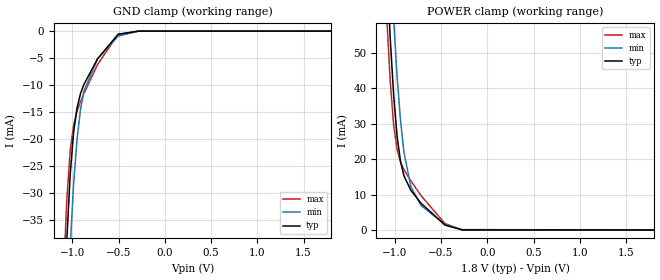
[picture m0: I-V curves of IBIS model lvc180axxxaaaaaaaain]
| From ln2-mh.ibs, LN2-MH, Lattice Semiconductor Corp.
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|   Model lvc180axxxaaaaaaaain
[Model] lvc180axxxaaaaaaaain
Model_type Input
Polarity   Non-Inverting
Enable   Active-High
Vinl =  0.630V
Vinh =  1.170V
C_comp   5.000pF   4.000pF   5.500pF
[Temperature Range]   25.000   0.125k   -40.000
[Voltage Range]   1.800V   1.710V   1.890V
[C Comp Corner]
C_comp   5.000pF   4.000pF   5.500pF
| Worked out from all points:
|   GND clamp passes 1 mA (typ) near -0.54 V on its own axis
|   POWER clamp passes 1 mA (typ) near -0.43 V on its own axis
[GND_clamp]
|Voltage   I(typ)   I(min)   I(max)
-1.8V     -593.8mA   -601.6mA   -589.9mA
-1.097V   -55.43mA   -73.28mA   -46.03mA
-1.06V    -38.82mA   -55.14mA   -31.31mA
-1.023V   -26.57mA   -40.02mA   -22.16mA
-986mV    -18.72mA   -28.32mA   -17.41mA
-949mV    -14.23mA   -20.04mA   -14.84mA
-912mV    -11.62mA   -14.6mA    -13.08mA
-875mV    -9.888mA   -11.17mA   -11.57mA
-727mV    -5.132mA   -5.103mA   -6.185mA
-505mV    -593.1uA   -941.9uA   -608.6uA
-283mV    -845.6nA   -11.06uA   -175.4nA
1.8V      0A         0A         0A
[POWER_clamp]
|Voltage   I(typ)   I(min)   I(max)
-1.789V   656.1mA    673.4mA    646.6mA
-1.086V   74.05mA    100.3mA    59.6mA
-1.049V   53.94mA    78.49mA    41.72mA
-1.012V   37.83mA    59.3mA     29.5mA
-975mV    26.39mA    43.25mA    22.68mA
-938mV    19.32mA    30.82mA    19.16mA
-901mV    15.29mA    21.92mA    17.03mA
-827mV    11.23mA    12.27mA    13.9mA
-716mV    7.541mA    6.911mA    9.687mA
-457mV    1.37mA     1.553mA    1.792mA
-272mV    21.09uA    99.55uA    12.56uA
1.8V      0A         0A         0A
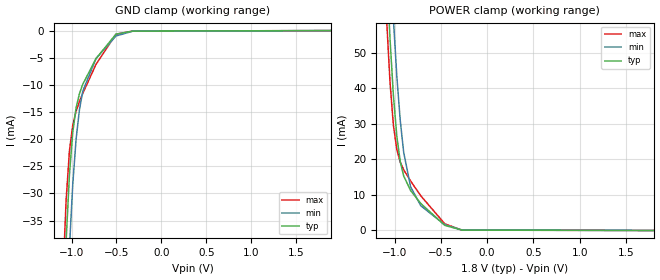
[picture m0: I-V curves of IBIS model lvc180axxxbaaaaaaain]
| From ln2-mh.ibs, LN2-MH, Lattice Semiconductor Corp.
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|   Model lvc180axxxbaaaaaaain
[Model] lvc180axxxbaaaaaaain
Model_type Input
Polarity   Non-Inverting
Enable   Active-High
Vinl =  0.630V
Vinh =  1.170V
C_comp   5.000pF   4.000pF   5.500pF
[Temperature Range]   25.000   0.125k   -40.000
[Voltage Range]   1.800V   1.710V   1.890V
[C Comp Corner]
C_comp   5.000pF   4.000pF   5.500pF
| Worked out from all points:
|   GND clamp passes 1 mA (typ) near -0.53 V on its own axis
|   POWER clamp passes 1 mA (typ) near -0.43 V on its own axis
[GND_clamp]
|Voltage   I(typ)   I(min)   I(max)
-1.8V     -593.8mA   -601.6mA   -589.9mA
-1.097V   -55.44mA   -73.29mA   -46.03mA
-1.06V    -38.82mA   -55.15mA   -31.31mA
-1.023V   -26.58mA   -40.03mA   -22.17mA
-986mV    -18.73mA   -28.33mA   -17.42mA
-949mV    -14.24mA   -20.05mA   -14.86mA
-912mV    -11.64mA   -14.62mA   -13.09mA
-875mV    -9.904mA   -11.18mA   -11.58mA
-727mV    -5.156mA   -5.128mA   -6.207mA
-505mV    -654.2uA   -995.8uA   -670.8uA
-320mV    -95.24uA   -117.6uA   -94.23uA
1.89V     0A         0A         0A
[POWER_clamp]
|Voltage   I(typ)   I(min)   I(max)
-1.789V   656.1mA    673.4mA    646.7mA
-1.086V   74.07mA    100.3mA    59.62mA
-1.049V   53.96mA    78.5mA     41.74mA
-1.012V   37.85mA    59.32mA    29.54mA
-975mV    26.42mA    43.27mA    22.72mA
-938mV    19.35mA    30.85mA    19.2mA
-901mV    15.32mA    21.94mA    17.08mA
-827mV    11.27mA    12.31mA    13.94mA
-716mV    7.586mA    6.949mA    9.737mA
-457mV    1.435mA    1.604mA    1.865mA
-272mV    94.61uA    156.5uA    102.5uA
1.8V      0A         0A         0A
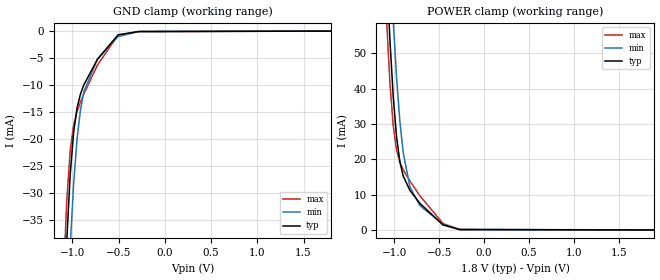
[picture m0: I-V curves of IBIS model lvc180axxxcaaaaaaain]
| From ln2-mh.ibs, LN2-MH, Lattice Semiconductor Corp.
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|   Model lvc180axxxcaaaaaaain
[Model] lvc180axxxcaaaaaaain
Model_type Input
Polarity   Non-Inverting
Enable   Active-High
Vinl =  0.630V
Vinh =  1.170V
C_comp   5.000pF   4.000pF   5.500pF
[Temperature Range]   25.000   0.125k   -40.000
[Voltage Range]   1.800V   1.710V   1.890V
[C Comp Corner]
C_comp   5.000pF   4.000pF   5.500pF
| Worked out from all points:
|   GND clamp passes 1 mA (typ) near -0.53 V on its own axis
|   POWER clamp passes 1 mA (typ) near -0.43 V on its own axis
[GND_clamp]
|Voltage   I(typ)   I(min)   I(max)
-1.8V     -593.8mA   -601.6mA   -589.9mA
-1.097V   -55.46mA   -73.3mA    -46.06mA
-1.06V    -38.85mA   -55.17mA   -31.35mA
-1.023V   -26.61mA   -40.05mA   -22.21mA
-986mV    -18.77mA   -28.35mA   -17.46mA
-949mV    -14.27mA   -20.07mA   -14.9mA
-912mV    -11.67mA   -14.64mA   -13.14mA
-875mV    -9.942mA   -11.21mA   -11.63mA
-727mV    -5.196mA   -5.156mA   -6.26mA
-505mV    -695uA     -1.018mA   -733.5uA
-283mV    -83.17uA   -81.38uA   -98.72uA
1.8V      0A         0A         0A
[POWER_clamp]
|Voltage   I(typ)   I(min)   I(max)
-1.789V   656.1mA    673.4mA    646.6mA
-1.086V   74.06mA    100.3mA    59.61mA
-1.049V   53.95mA    78.5mA     41.72mA
-1.012V   37.83mA    59.31mA    29.51mA
-975mV    26.4mA     43.26mA    22.69mA
-938mV    19.33mA    30.83mA    19.17mA
-901mV    15.3mA     21.93mA    17.04mA
-827mV    11.24mA    12.29mA    13.91mA
-716mV    7.56mA     6.932mA    9.703mA
-457mV    1.417mA    1.598mA    1.834mA
-272mV    110.3uA    182.5uA    103.2uA
1.89V     0A         0A         0A
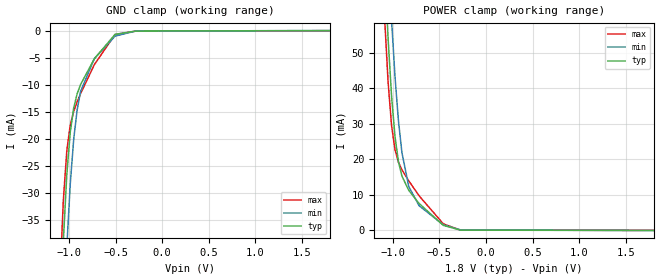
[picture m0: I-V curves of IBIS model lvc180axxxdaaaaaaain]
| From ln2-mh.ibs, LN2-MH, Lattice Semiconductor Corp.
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|   Model lvc180axxxdaaaaaaain
[Model] lvc180axxxdaaaaaaain
Model_type Input
Polarity   Non-Inverting
Enable   Active-High
Vinl =  0.630V
Vinh =  1.170V
C_comp   5.000pF   4.000pF   5.500pF
[Temperature Range]   25.000   0.125k   -40.000
[Voltage Range]   1.800V   1.710V   1.890V
[C Comp Corner]
C_comp   5.000pF   4.000pF   5.500pF
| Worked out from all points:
|   GND clamp passes 1 mA (typ) near -0.53 V on its own axis
|   POWER clamp passes 1 mA (typ) near -0.43 V on its own axis
[GND_clamp]
|Voltage   I(typ)   I(min)   I(max)
-1.8V     -593.8mA   -601.6mA   -589.9mA
-1.097V   -55.46mA   -73.3mA    -46.06mA
-1.06V    -38.85mA   -55.17mA   -31.35mA
-1.023V   -26.61mA   -40.05mA   -22.21mA
-986mV    -18.77mA   -28.35mA   -17.46mA
-949mV    -14.27mA   -20.07mA   -14.9mA
-912mV    -11.67mA   -14.64mA   -13.14mA
-875mV    -9.942mA   -11.21mA   -11.63mA
-727mV    -5.196mA   -5.156mA   -6.26mA
-505mV    -695uA     -1.018mA   -733.5uA
-283mV    -83.17uA   -81.38uA   -98.72uA
1.8V      -13.14nA   0A         -27.62uA
[POWER_clamp]
|Voltage   I(typ)   I(min)   I(max)
-1.789V   656.1mA    673.4mA    646.7mA
-1.086V   74.07mA    100.3mA    59.62mA
-1.049V   53.96mA    78.5mA     41.74mA
-1.012V   37.85mA    59.32mA    29.54mA
-975mV    26.42mA    43.27mA    22.72mA
-938mV    19.35mA    30.85mA    19.2mA
-901mV    15.32mA    21.94mA    17.08mA
-827mV    11.27mA    12.31mA    13.94mA
-716mV    7.586mA    6.949mA    9.737mA
-457mV    1.435mA    1.604mA    1.865mA
-272mV    94.61uA    156.5uA    102.5uA
1.8V      0A         0A         28.48uA
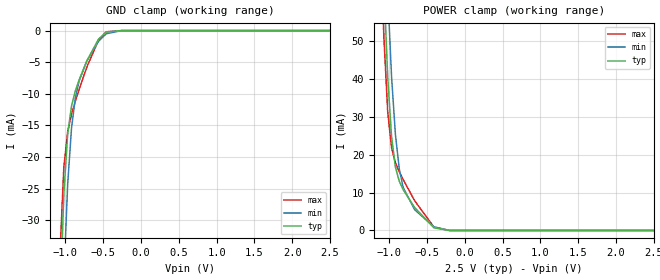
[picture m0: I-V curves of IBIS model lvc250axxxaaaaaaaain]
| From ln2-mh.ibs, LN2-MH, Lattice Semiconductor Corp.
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|   Model lvc250axxxaaaaaaaain
[Model] lvc250axxxaaaaaaaain
Model_type Input
Polarity   Non-Inverting
Enable   Active-High
Vinl =  0.700V
Vinh =  1.700V
C_comp   5.000pF   4.000pF   5.500pF
[Temperature Range]   25.000   0.125k   -40.000
[Voltage Range]   2.500V   2.380V   2.630V
[C Comp Corner]
C_comp   5.000pF   4.000pF   5.500pF
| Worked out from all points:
|   GND clamp passes 1 mA (typ) near -0.54 V on its own axis
|   POWER clamp passes 1 mA (typ) near -0.43 V on its own axis
[GND_clamp]
|Voltage   I(typ)   I(min)   I(max)
-2.5V     -1.192A    -1.195A    -1.19A
-1.072V   -43.75mA   -60.69mA   -35.41mA
-1.021V   -25.99mA   -39.29mA   -21.7mA
-970mV    -16.38mA   -24.32mA   -16mA
-919mV    -11.94mA   -15.42mA   -13.24mA
-868mV    -9.525mA   -10.63mA   -11.17mA
-817mV    -7.753mA   -7.942mA   -9.278mA
-715mV    -4.764mA   -4.767mA   -5.735mA
-562mV    -1.351mA   -1.698mA   -1.532mA
-460mV    -227.7uA   -505.8uA   -189.7uA
-256mV    -345.3nA   -5.519uA   -58.82nA
2.5V      0A         0A         0A
[POWER_clamp]
|Voltage   I(typ)   I(min)   I(max)
-2.498V   1.304A     1.316A     1.297A
-1.121V   95.94mA    122.8mA    80.58mA
-1.07V    64.94mA    90.54mA    51.24mA
-1.019V   40.52mA    62.72mA    31.37mA
-968mV    24.75mA    40.65mA    21.85mA
-917mV    16.76mA    25.36mA    17.89mA
-866mV    13.01mA    16.28mA    15.51mA
-815mV    10.8mA     11.39mA    13.48mA
-662mV    6.034mA    5.465mA    7.841mA
-407mV    709.3uA    963.6uA    895.3uA
-203mV    1.87uA     18.14uA    588nA
2.5V      0A         0A         0A
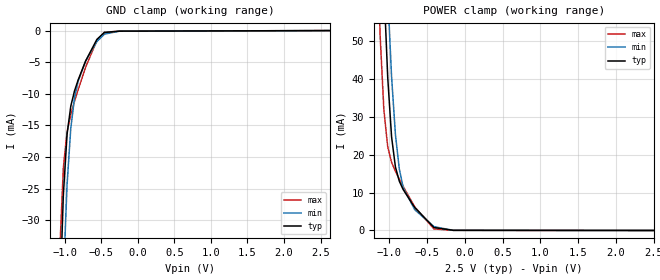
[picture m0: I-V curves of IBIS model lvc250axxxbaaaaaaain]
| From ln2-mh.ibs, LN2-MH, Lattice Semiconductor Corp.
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|   Model lvc250axxxbaaaaaaain
[Model] lvc250axxxbaaaaaaain
Model_type Input
Polarity   Non-Inverting
Enable   Active-High
Vinl =  0.700V
Vinh =  1.700V
C_comp   5.000pF   4.000pF   5.500pF
[Temperature Range]   25.000   0.125k   -40.000
[Voltage Range]   2.500V   2.380V   2.630V
[C Comp Corner]
C_comp   5.000pF   4.000pF   5.500pF
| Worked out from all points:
|   GND clamp passes 1 mA (typ) near -0.53 V on its own axis
|   POWER clamp passes 1 mA (typ) near -0.42 V on its own axis
[GND_clamp]
|Voltage   I(typ)   I(min)   I(max)
-2.5V     -1.192A    -1.195A    -1.19A
-1.072V   -43.76mA   -60.69mA   -35.42mA
-1.021V   -26mA      -39.3mA    -21.71mA
-970mV    -16.39mA   -24.33mA   -16.01mA
-919mV    -11.95mA   -15.43mA   -13.26mA
-868mV    -9.541mA   -10.65mA   -11.19mA
-817mV    -7.772mA   -7.962mA   -9.295mA
-715mV    -4.79mA    -4.793mA   -5.758mA
-562mV    -1.398mA   -1.741mA   -1.577mA
-460mV    -303uA     -570.5uA   -268.1uA
-256mV    -93.09uA   -97.56uA   -93.82uA
2.63V     0A         0A         0A
[POWER_clamp]
|Voltage   I(typ)   I(min)   I(max)
-2.498V   1.304A     1.316A     1.252A
-1.121V   95.95mA    122.8mA    52.26mA
-1.07V    64.96mA    90.55mA    31.97mA
-1.019V   40.55mA    62.74mA    22.12mA
-968mV    24.78mA    40.67mA    18.05mA
-917mV    16.8mA     25.38mA    15.64mA
-866mV    13.05mA    16.31mA    13.61mA
-815mV    10.84mA    11.42mA    11.66mA
-662mV    6.081mA    5.505mA    6.248mA
-407mV    780.9uA    1.018mA    403.1uA
-152mV    41.74uA    39.57uA    33.52uA
2.5V      0A         0A         0A
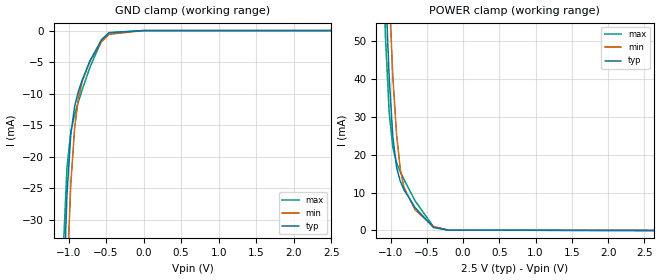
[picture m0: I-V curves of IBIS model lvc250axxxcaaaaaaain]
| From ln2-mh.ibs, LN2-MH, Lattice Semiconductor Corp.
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|   Model lvc250axxxcaaaaaaain
[Model] lvc250axxxcaaaaaaain
Model_type Input
Polarity   Non-Inverting
Enable   Active-High
Vinl =  0.700V
Vinh =  1.700V
C_comp   5.000pF   4.000pF   5.500pF
[Temperature Range]   25.000   0.125k   -40.000
[Voltage Range]   2.500V   2.380V   2.630V
[C Comp Corner]
C_comp   5.000pF   4.000pF   5.500pF
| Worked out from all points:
|   GND clamp passes 1 mA (typ) near -0.53 V on its own axis
|   POWER clamp passes 1 mA (typ) near -0.42 V on its own axis
[GND_clamp]
|Voltage   I(typ)   I(min)   I(max)
-2.5V     -1.192A    -1.195A    -1.19A
-1.072V   -43.78mA   -60.71mA   -35.45mA
-1.021V   -26.03mA   -39.32mA   -21.75mA
-970mV    -16.43mA   -24.35mA   -16.06mA
-919mV    -11.99mA   -15.46mA   -13.3mA
-868mV    -9.579mA   -10.68mA   -11.24mA
-817mV    -7.81mA    -7.99mA    -9.346mA
-715mV    -4.829mA   -4.821mA   -5.811mA
-562mV    -1.439mA   -1.766mA   -1.637mA
-460mV    -340.1uA   -588uA     -329.6uA
-1mV      -322.6nA   -546.3nA   -344.6nA
2.5V      0A         0A         0A
[POWER_clamp]
|Voltage   I(typ)   I(min)   I(max)
-2.498V   1.304A     1.316A     1.297A
-1.121V   95.94mA    122.8mA    80.59mA
-1.07V    64.94mA    90.54mA    51.24mA
-1.019V   40.53mA    62.73mA    31.37mA
-968mV    24.76mA    40.66mA    21.86mA
-917mV    16.77mA    25.37mA    17.9mA
-866mV    13.02mA    16.29mA    15.53mA
-815mV    10.81mA    11.4mA     13.5mA
-662mV    6.057mA    5.49mA     7.861mA
-407mV    767.3uA    1.018mA    949.7uA
-203mV    93.35uA    107.9uA    92.84uA
2.63V     0A         0A         0A
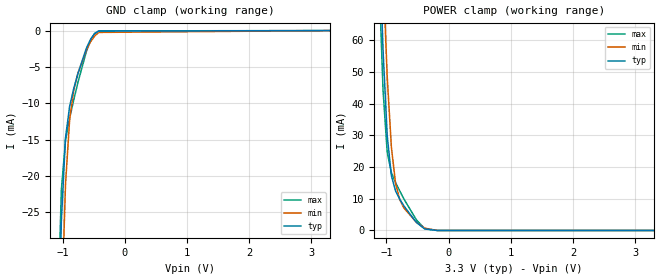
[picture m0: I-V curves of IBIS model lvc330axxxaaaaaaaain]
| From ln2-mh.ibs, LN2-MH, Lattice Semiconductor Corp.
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|   Model lvc330axxxaaaaaaaain
[Model] lvc330axxxaaaaaaaain
Model_type Input
Polarity   Non-Inverting
Enable   Active-High
Vinl =  0.800V
Vinh =  2.000V
C_comp   5.000pF   4.000pF   5.500pF
[Temperature Range]   25.000   0.125k   -40.000
[Voltage Range]   3.300V   3.140V   3.470V
[C Comp Corner]
C_comp   5.000pF   4.000pF   5.500pF
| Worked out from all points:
|   GND clamp passes 1 mA (typ) near -0.54 V on its own axis
|   POWER clamp passes 1 mA (typ) near -0.43 V on its own axis
[GND_clamp]
|Voltage   I(typ)   I(min)   I(max)
-3.3V     -1.888A    -1.888A    -1.884A
-1.089V   -51.51mA   -69.13mA   -42.36mA
-1.022V   -26.27mA   -39.65mA   -21.92mA
-955mV    -14.73mA   -21.14mA   -15.11mA
-888mV    -10.38mA   -12.17mA   -12.02mA
-821mV    -7.911mA   -8.124mA   -9.484mA
-754mV    -5.878mA   -5.822mA   -7.087mA
-620mV    -2.453mA   -2.701mA   -2.895mA
-553mV    -1.209mA   -1.563mA   -1.356mA
-486mV    -407.8uA   -735.6uA   -389uA
-419mV    -74.09uA   -251uA     -44.51uA
3.3V      0A         0A         0A
[POWER_clamp]
|Voltage   I(typ)   I(min)   I(max)
-3.266V   2.018A     2.026A     2.011A
-1.122V   96.65mA    123.5mA    81.29mA
-1.055V   57.01mA    81.9mA     44.37mA
-988mV    29.96mA    48.56mA    24.75mA
-921mV    17.31mA    26.37mA    18.28mA
-854mV    12.53mA    14.91mA    15.15mA
-787mV    9.913mA    9.785mA    12.51mA
-720mV    7.777mA    7.123mA    9.98mA
-519mV    2.548mA    2.55mA     3.358mA
-385mV    484uA      741.5uA    589.3uA
-184mV    1.02uA     11.17uA    291.2nA
3.3V      0A         0A         0A
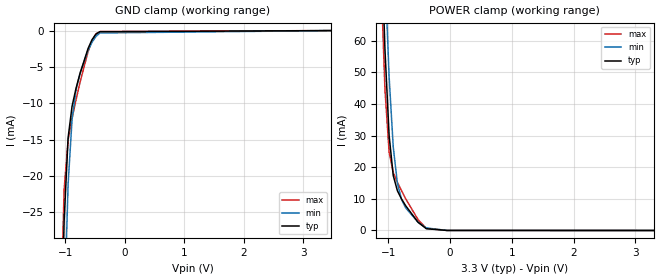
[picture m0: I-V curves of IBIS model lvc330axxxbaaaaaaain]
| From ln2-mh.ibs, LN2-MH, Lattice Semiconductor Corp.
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|   Model lvc330axxxbaaaaaaain
[Model] lvc330axxxbaaaaaaain
Model_type Input
Polarity   Non-Inverting
Enable   Active-High
Vinl =  0.800V
Vinh =  2.000V
C_comp   5.000pF   4.000pF   5.500pF
[Temperature Range]   25.000   0.125k   -40.000
[Voltage Range]   3.300V   3.140V   3.470V
[C Comp Corner]
C_comp   5.000pF   4.000pF   5.500pF
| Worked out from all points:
|   GND clamp passes 1 mA (typ) near -0.53 V on its own axis
|   POWER clamp passes 1 mA (typ) near -0.42 V on its own axis
[GND_clamp]
|Voltage   I(typ)   I(min)   I(max)
-3.3V     -1.888A    -1.888A    -1.884A
-1.089V   -51.51mA   -69.14mA   -42.37mA
-1.022V   -26.28mA   -39.66mA   -21.93mA
-955mV    -14.75mA   -21.16mA   -15.12mA
-888mV    -10.4mA    -12.19mA   -12.04mA
-821mV    -7.931mA   -8.144mA   -9.504mA
-754mV    -5.902mA   -5.847mA   -7.11mA
-620mV    -2.489mA   -2.736mA   -2.929mA
-553mV    -1.258mA   -1.608mA   -1.404mA
-486mV    -475.1uA   -794uA     -458uA
-419mV    -159.8uA   -326.1uA   -133.8uA
3.47V     0A         0A         0A
[POWER_clamp]
|Voltage   I(typ)   I(min)   I(max)
-3.266V   2.018A     2.026A     2.011A
-1.122V   96.67mA    123.5mA    81.31mA
-1.055V   57.03mA    81.91mA    44.39mA
-988mV    29.99mA    48.58mA    24.79mA
-921mV    17.35mA    26.39mA    18.32mA
-854mV    12.57mA    14.94mA    15.2mA
-787mV    9.955mA    9.821mA    12.56mA
-720mV    7.821mA    7.161mA    10.03mA
-519mV    2.605mA    2.596mA    3.423mA
-385mV    558.9uA    797uA      677.4uA
-50mV     13.41uA    11.82uA    16.07uA
3.3V      0A         0A         0A
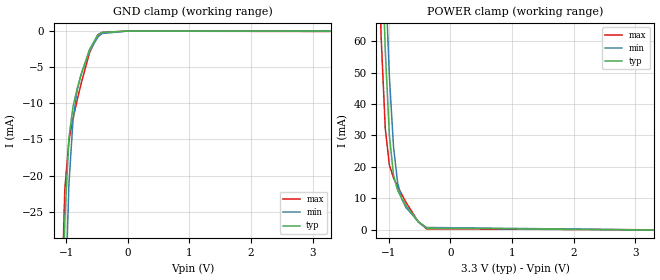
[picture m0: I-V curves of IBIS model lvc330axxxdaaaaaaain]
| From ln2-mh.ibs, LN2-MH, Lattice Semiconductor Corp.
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|   Model lvc330axxxdaaaaaaain
[Model] lvc330axxxdaaaaaaain
Model_type Input
Polarity   Non-Inverting
Enable   Active-High
Vinl =  0.800V
Vinh =  2.000V
C_comp   5.000pF   4.000pF   5.500pF
[Temperature Range]   25.000   0.125k   -40.000
[Voltage Range]   3.300V   3.140V   3.470V
[C Comp Corner]
C_comp   5.000pF   4.000pF   5.500pF
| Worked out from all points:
|   GND clamp passes 1 mA (typ) near -0.53 V on its own axis
|   POWER clamp passes 1 mA (typ) near -0.42 V on its own axis
[GND_clamp]
|Voltage   I(typ)   I(min)   I(max)
-3.3V     -1.888A    -1.888A    -1.884A
-1.089V   -51.53mA   -69.15mA   -42.39mA
-1.022V   -26.3mA    -39.68mA   -21.97mA
-955mV    -14.78mA   -21.18mA   -15.17mA
-888mV    -10.43mA   -12.22mA   -12.09mA
-821mV    -7.968mA   -8.171mA   -9.552mA
-754mV    -5.939mA   -5.874mA   -7.16mA
-620mV    -2.529mA   -2.762mA   -2.986mA
-486mV    -514.7uA   -814.1uA   -521uA
-419mV    -189.1uA   -337.4uA   -186.7uA
-17mV     -4.857uA   -4.628uA   -5.666uA
3.3V      -228.2nA   0A         -51.2uA
[POWER_clamp]
|Voltage   I(typ)   I(min)   I(max)
-3.266V   2.018A     2.026A     1.981A
-1.189V   143.8mA    170.5mA    104.3mA
-1.122V   96.67mA    123.5mA    61.29mA
-1.055V   57.03mA    81.91mA    32.26mA
-988mV    29.99mA    48.58mA    20.59mA
-921mV    17.35mA    26.39mA    16.54mA
-854mV    12.57mA    14.94mA    13.81mA
-787mV    9.955mA    9.821mA    11.28mA
-720mV    7.821mA    7.161mA    8.829mA
-519mV    2.605mA    2.596mA    2.57mA
-385mV    558.9uA    797uA      357.4uA
3.3V      0A         0A         51.61uA
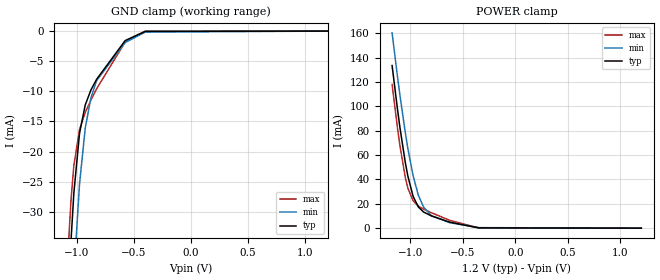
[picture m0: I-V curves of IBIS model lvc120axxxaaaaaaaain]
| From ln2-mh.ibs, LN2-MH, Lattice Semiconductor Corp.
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|   Model lvc120axxxaaaaaaaain
[Model] lvc120axxxaaaaaaaain
Model_type Input
Polarity   Non-Inverting
Enable   Active-High
Vinl =  0.420V
Vinh =  0.780V
C_comp   5.000pF   4.000pF   5.500pF
[Temperature Range]   25.000   0.125k   -40.000
[Voltage Range]   1.200V   1.140V   1.260V
[C Comp Corner]
C_comp   5.000pF   4.000pF   5.500pF
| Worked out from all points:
|   GND clamp passes 1 mA (typ) near -0.54 V on its own axis
|   POWER clamp passes 1 mA (typ) near -0.43 V on its own axis
[GND_clamp]
|Voltage   I(typ)   I(min)   I(max)
-1.2V     -117.2mA   -135mA     -107.6mA
-1.1V     -56.86mA   -74.77mA   -47.33mA
-1.075V   -44.97mA   -62.07mA   -36.48mA
-1.05V    -34.95mA   -50.63mA   -28.14mA
-1.025V   -26.98mA   -40.64mA   -22.36mA
-975mV    -16.96mA   -25.39mA   -16.34mA
-925mV    -12.26mA   -16.11mA   -13.51mA
-875mV    -9.771mA   -11.05mA   -11.44mA
-825mV    -7.989mA   -8.223mA   -9.563mA
-575mV    -1.572mA   -1.892mA   -1.811mA
-400mV    -42.89uA   -174.2uA   -23.24uA
1.2V      54.17pA    0A         0A
[POWER_clamp]
|Voltage   I(typ)   I(min)   I(max)
-1.175V   133.4mA    160.2mA    117.9mA
-1.125V   98.47mA    125.3mA    83.04mA
-1.1V     82.4mA     108.9mA    67.43mA
-1.05V    54.25mA    78.88mA    41.92mA
-1.025V   42.77mA    65.54mA    32.88mA
-975mV    26.16mA    43.08mA    22.4mA
-925mV    17.39mA    27.08mA    18.05mA
-875mV    13.26mA    17.28mA    15.6mA
-800mV    10.04mA    10.22mA    12.64mA
-625mV    4.901mA    4.474mA    6.406mA
-350mV    221.2uA    440uA      240.2uA
1.2V      0A         0A         0A
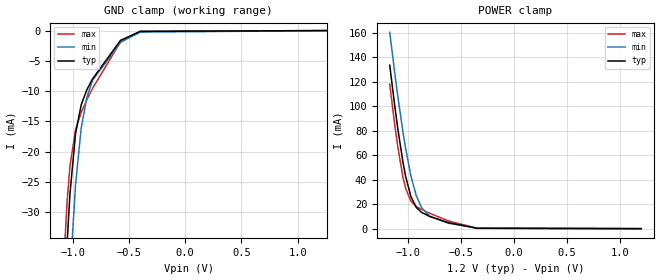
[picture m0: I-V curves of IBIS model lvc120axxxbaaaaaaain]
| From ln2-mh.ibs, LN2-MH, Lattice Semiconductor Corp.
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|   Model lvc120axxxbaaaaaaain
[Model] lvc120axxxbaaaaaaain
Model_type Input
Polarity   Non-Inverting
Enable   Active-High
Vinl =  0.420V
Vinh =  0.780V
C_comp   5.000pF   4.000pF   5.500pF
[Temperature Range]   25.000   0.125k   -40.000
[Voltage Range]   1.200V   1.140V   1.260V
[C Comp Corner]
C_comp   5.000pF   4.000pF   5.500pF
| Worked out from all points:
|   GND clamp passes 1 mA (typ) near -0.53 V on its own axis
|   POWER clamp passes 1 mA (typ) near -0.43 V on its own axis
[GND_clamp]
|Voltage   I(typ)   I(min)   I(max)
-1.2V     -117.2mA   -135mA     -107.6mA
-1.1V     -56.86mA   -74.78mA   -47.33mA
-1.075V   -44.98mA   -62.07mA   -36.48mA
-1.05V    -34.95mA   -50.64mA   -28.16mA
-1.025V   -26.99mA   -40.65mA   -22.37mA
-975mV    -16.97mA   -25.4mA    -16.35mA
-925mV    -12.28mA   -16.12mA   -13.52mA
-875mV    -9.786mA   -11.06mA   -11.45mA
-825mV    -8.006mA   -8.242mA   -9.578mA
-575mV    -1.614mA   -1.931mA   -1.851mA
-400mV    -128.6uA   -250.2uA   -111.6uA
1.26V     0A         0A         0A
[POWER_clamp]
|Voltage   I(typ)   I(min)   I(max)
-1.175V   133.4mA    160.2mA    117.9mA
-1.125V   98.48mA    125.3mA    83.05mA
-1.1V     82.42mA    109mA      67.45mA
-1.05V    54.27mA    78.9mA     41.95mA
-1.025V   42.79mA    65.55mA    32.91mA
-975mV    26.19mA    43.1mA     22.44mA
-925mV    17.43mA    27.1mA     18.09mA
-875mV    13.3mA     17.31mA    15.65mA
-800mV    10.08mA    10.25mA    12.68mA
-625mV    4.949mA    4.514mA    6.461mA
-350mV    298.6uA    495.9uA    334.2uA
1.2V      0A         0A         0A
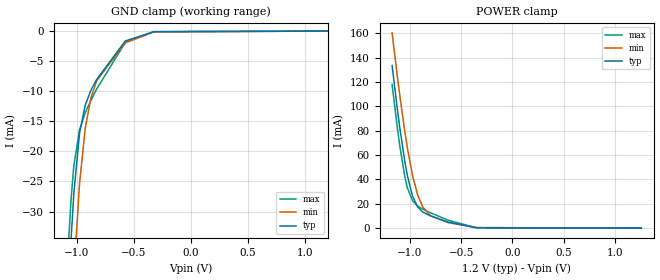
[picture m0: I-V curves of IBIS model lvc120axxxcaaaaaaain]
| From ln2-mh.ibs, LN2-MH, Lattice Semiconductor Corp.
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|   Model lvc120axxxcaaaaaaain
[Model] lvc120axxxcaaaaaaain
Model_type Input
Polarity   Non-Inverting
Enable   Active-High
Vinl =  0.420V
Vinh =  0.780V
C_comp   5.000pF   4.000pF   5.500pF
[Temperature Range]   25.000   0.125k   -40.000
[Voltage Range]   1.200V   1.140V   1.260V
[C Comp Corner]
C_comp   5.000pF   4.000pF   5.500pF
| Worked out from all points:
|   GND clamp passes 1 mA (typ) near -0.53 V on its own axis
|   POWER clamp passes 1 mA (typ) near -0.43 V on its own axis
[GND_clamp]
|Voltage   I(typ)   I(min)   I(max)
-1.2V     -117.3mA   -135mA     -107.6mA
-1.1V     -56.88mA   -74.79mA   -47.36mA
-1.075V   -45mA      -62.09mA   -36.51mA
-1.05V    -34.98mA   -50.66mA   -28.19mA
-1.025V   -27.02mA   -40.67mA   -22.41mA
-975mV    -17.01mA   -25.43mA   -16.4mA
-925mV    -12.31mA   -16.15mA   -13.57mA
-875mV    -9.824mA   -11.09mA   -11.5mA
-825mV    -8.045mA   -8.27mA    -9.63mA
-575mV    -1.656mA   -1.957mA   -1.911mA
-325mV    -96.48uA   -108.8uA   -113uA
1.2V      0A         0A         0A
[POWER_clamp]
|Voltage   I(typ)   I(min)   I(max)
-1.175V   133.4mA    160.2mA    117.9mA
-1.125V   98.47mA    125.3mA    83.04mA
-1.1V     82.41mA    108.9mA    67.44mA
-1.05V    54.26mA    78.89mA    41.93mA
-1.025V   42.78mA    65.54mA    32.88mA
-975mV    26.17mA    43.08mA    22.41mA
-925mV    17.4mA     27.09mA    18.06mA
-875mV    13.27mA    17.29mA    15.61mA
-800mV    10.05mA    10.23mA    12.65mA
-625mV    4.925mA    4.5mA      6.427mA
-350mV    294.1uA    504.6uA    312.4uA
1.26V     0A         0A         0A
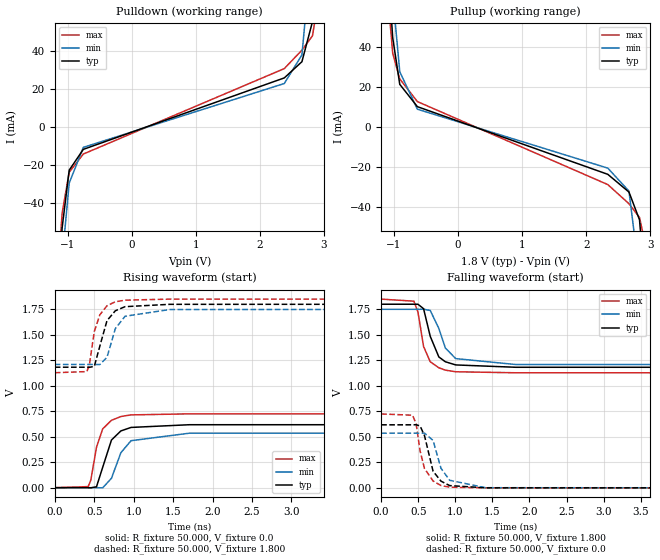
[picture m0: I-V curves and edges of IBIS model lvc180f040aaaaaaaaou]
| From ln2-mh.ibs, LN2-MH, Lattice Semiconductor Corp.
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|   Model lvc180f040aaaaaaaaou
[Model] lvc180f040aaaaaaaaou
Model_type Output
Polarity   Non-Inverting
Enable   Active-High
Vmeas =  0.900V
Cref =  0.0F
Rref =  1.000M
Vref =  0.0V
C_comp   5.000pF   4.000pF   5.500pF
[Temperature Range]   25.000   0.125k   -40.000
[Voltage Range]   1.800V   1.750V   1.850V
[C Comp Corner]
C_comp   5.000pF   4.000pF   5.500pF
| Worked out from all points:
|   slope of the pulldown table from 0 to 0.27 V, typ, clamps not added: 97.6 ohm
|   slope of the pullup table from 0 to 0.27 V, typ, clamps not added: 97.7 ohm
|   rising waveform, R_fixture 50.000, V_fixture 0.0: 20-80 % time 157ps typ, 190ps min, 135ps max; typ from 0 V to 0.618 V
|   rising waveform, R_fixture 50.000, V_fixture 1.800: 20-80 % time 139ps typ, 157ps min, 126ps max; typ from 1.18 V to 1.8 V
|   falling waveform, R_fixture 50.000, V_fixture 1.800: 20-80 % time 144ps typ, 170ps min, 127ps max; typ from 1.8 V to 1.18 V
|   falling waveform, R_fixture 50.000, V_fixture 0.0: 20-80 % time 144ps typ, 161ps min, 132ps max; typ from 0.618 V to 0 V
[Pulldown]
|Voltage   I(typ)   I(min)   I(max)
-1.8V     -594.9mA   -602.6mA   -591.2mA
-1.195V   -116.2mA   -133.8mA   -106.9mA
-1.14V    -81.89mA   -99.71mA   -72.47mA
-1.085V   -53.29mA   -69.9mA    -45.55mA
-975mV    -22.88mA   -29.74mA   -23.99mA
-755mV    -11.87mA   -10.81mA   -14.34mA
2.38V     25.94mA    22.97mA    30.86mA
2.655V    34.5mA     38.12mA    40.62mA
2.82V     55.71mA    98.51mA    48.22mA
2.93V     109.9mA    169.2mA    71.45mA
2.985V    147.2mA    209.4mA    100.1mA
3.6V      668.3mA    729.8mA    614.2mA
[Pullup]
|Voltage   I(typ)   I(min)   I(max)
-1.8V     666.6mA    683.8mA    657.3mA
-1.13V    103.9mA    130.4mA    88.94mA
-1.075V   70.36mA    95.55mA    57.33mA
-1.02V    44.5mA     65.73mA    36.8mA
-910mV    21.26mA    27.55mA    23.96mA
-635mV    10.12mA    8.855mA    12.65mA
2.335V    -23.67mA   -20.57mA   -28.79mA
2.665V    -32.52mA   -32.05mA   -38.34mA
2.83V     -46.45mA   -74.63mA   -45.25mA
2.94V     -89.38mA   -135.4mA   -61.6mA
2.995V    -122.2mA   -171.5mA   -85.2mA
3.6V      -597.5mA   -646.3mA   -552.4mA
[Ramp]
| variable   typ   min   max
dV/dt_r   0.371/0.157n   0.322/0.190n   0.435/0.135n
dV/dt_f   0.371/0.144n   0.325/0.170n   0.433/0.127n
R_load = 50.000
[Rising Waveform]
R_fixture= 50.000
V_fixture= 0.0
V_fixture_min= 0.0
V_fixture_max= 0.0
|time   V(typ)   V(min)   V(max)
0s        817.7nV    7.236uV    251.1nV
423ps     -13.81uV   -70.9uV    10.47mV
457ps     -1.411mV   -5.095uV   74.25mV
529ps     8.791mV    -98.04uV   396.8mV
607ps     199mV      -1.754mV   576.5mV
719ps     467.9mV    92.76mV    661.3mV
838ps     556.9mV    343.1mV    698.4mV
967ps     591.2mV    461mV      714.2mV
1.707ns   617.7mV    534.7mV    724.4mV
10ns      617.9mV    535.8mV    724.4mV
[Rising Waveform]
R_fixture= 50.000
V_fixture= 1.800
V_fixture_min= 1.750
V_fixture_max= 1.850
|time   V(typ)   V(min)   V(max)
0s        1.182V     1.209V     1.128V
407ps     1.182V     1.209V     1.139V
439ps     1.181V     1.209V     1.207V
501ps     1.19V      1.209V     1.532V
571ps     1.388V     1.208V     1.696V
662ps     1.639V     1.279V     1.785V
768ps     1.736V     1.561V     1.824V
891ps     1.776V     1.682V     1.84V
1.457ns   1.799V     1.748V     1.85V
10ns      1.8V       1.75V      1.85V
[Falling Waveform]
R_fixture= 50.000
V_fixture= 1.800
V_fixture_min= 1.750
V_fixture_max= 1.850
|time   V(typ)   V(min)   V(max)
0s        1.8V       1.75V      1.85V
441ps     1.8V       1.75V      1.83V
496ps     1.8V       1.75V      1.724V
572ps     1.756V     1.751V     1.385V
662ps     1.485V     1.739V     1.236V
778ps     1.283V     1.562V     1.177V
866ps     1.236V     1.371V     1.154V
1.005ns   1.205V     1.267V     1.138V
1.816ns   1.182V     1.209V     1.128V
10ns      1.182V     1.209V     1.128V
[Falling Waveform]
R_fixture= 50.000
V_fixture= 0.0
V_fixture_min= 0.0
V_fixture_max= 0.0
|time   V(typ)   V(min)   V(max)
0s        617.9mV    535.8mV    724.4mV
424ps     617.9mV    535.7mV    712mV
472ps     618.9mV    535.8mV    626.8mV
525ps     606.9mV    535.9mV    360.6mV
584ps     512.4mV    536.6mV    190.8mV
700ps     163.3mV    464.9mV    67.38mV
807ps     65.62mV    191.2mV    22.62mV
924ps     22.16mV    74.19mV    6.817mV
1.407ns   353.7uV    1.482mV    104.9uV
10ns      12.82uV    23.46uV    7.881uV
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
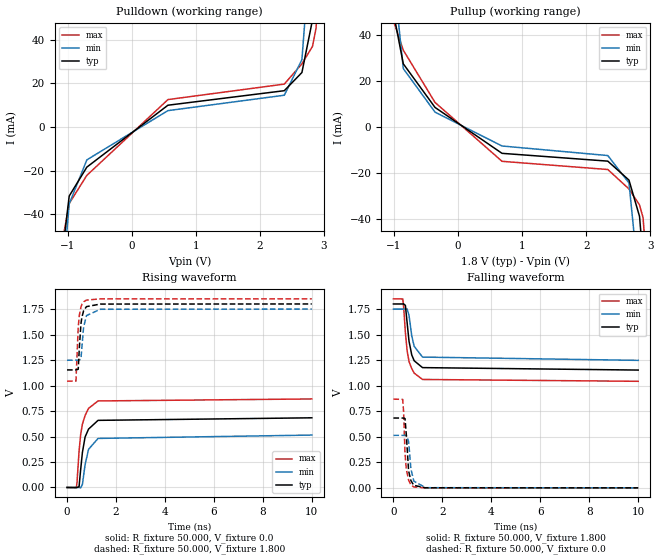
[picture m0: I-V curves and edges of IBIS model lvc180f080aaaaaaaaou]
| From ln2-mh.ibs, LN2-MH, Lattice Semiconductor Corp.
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|   Model lvc180f080aaaaaaaaou
[Model] lvc180f080aaaaaaaaou
Model_type Output
Polarity   Non-Inverting
Enable   Active-High
Vmeas =  0.900V
Cref =  0.0F
Rref =  1.000M
Vref =  0.0V
C_comp   5.000pF   4.000pF   5.500pF
[Temperature Range]   25.000   0.125k   -40.000
[Voltage Range]   1.800V   1.750V   1.850V
[C Comp Corner]
C_comp   5.000pF   4.000pF   5.500pF
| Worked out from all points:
|   slope of the pulldown table from 0 to 0.27 V, typ, clamps not added: 49.4 ohm
|   slope of the pullup table from 0 to 0.27 V, typ, clamps not added: 48.8 ohm
|   rising waveform, R_fixture 50.000, V_fixture 0.0: 20-80 % time 273ps typ, 277ps min, 281ps max; typ from 0 V to 0.683 V
|   rising waveform, R_fixture 50.000, V_fixture 1.800: 20-80 % time 119ps typ, 141ps min, 105ps max; typ from 1.15 V to 1.8 V
|   falling waveform, R_fixture 50.000, V_fixture 1.800: 20-80 % time 233ps typ, 248ps min, 237ps max; typ from 1.8 V to 1.15 V
|   falling waveform, R_fixture 50.000, V_fixture 0.0: 20-80 % time 120ps typ, 141ps min, 107ps max; typ from 0.684 V to 0 V
[Pulldown]
|Voltage   I(typ)   I(min)   I(max)
-1.8V     -595.2mA   -602.9mA   -591.4mA
-1.14V    -85.93mA   -102.5mA   -77.56mA
-1.085V   -58.79mA   -73.44mA   -52.97mA
-975mV    -31.59mA   -35.21mA   -34.99mA
-700mV    -18.35mA   -15.02mA   -22.12mA
565mV     10.01mA    7.529mA    12.59mA
2.38V     16.66mA    14.58mA    19.68mA
2.655V    24.98mA    30.9mA     28.97mA
2.82V     49.1mA     94.77mA    36.95mA
2.875V    73.68mA    128.8mA    45.22mA
2.985V    144.3mA    207.3mA    95.51mA
3.6V      667.3mA    728.9mA    613mA
[Pullup]
|Voltage   I(typ)   I(min)   I(max)
-1.8V     667mA      684.1mA    657.9mA
-1.075V   75.25mA    98.4mA     64.53mA
-1.02V    51.35mA    69.47mA    47.14mA
-855mV    27.49mA    25.43mA    33.42mA
-360mV    8.539mA    6.483mA    10.71mA
685mV     -11.42mA   -8.227mA   -14.89mA
2.335V    -14.81mA   -12.38mA   -18.45mA
2.665V    -23.05mA   -24.29mA   -26.89mA
2.83V     -38.84mA   -70.02mA   -33.87mA
2.885V    -57.42mA   -98.88mA   -39.4mA
2.995V    -118.7mA   -168.9mA   -79.65mA
3.6V      -596mA     -645mA     -550.6mA
[Ramp]
| variable   typ   min   max
dV/dt_r   0.410/0.273n   0.308/0.278n   0.521/0.281n
dV/dt_f   0.388/0.233n   0.301/0.249n   0.484/0.237n
R_load = 50.000
[Rising Waveform]
R_fixture= 50.000
V_fixture= 0.0
V_fixture_min= 0.0
V_fixture_max= 0.0
|time   V(typ)   V(min)   V(max)
0s        838.4nV    7.983uV    249.4nV
381ps     22.78uV    -82.28uV   -3.395mV
407ps     161.6uV    -82.59uV   46.74mV
491ps     6.619mV    120.9uV    352.2mV
556ps     172.5mV    -3.607mV   516.8mV
629ps     344mV      29.85mV    621.2mV
738ps     494.8mV    223.4mV    705.8mV
880ps     572.8mV    374.3mV    776.5mV
1.268ns   658.4mV    481.2mV    848.7mV
10ns      683.4mV    514mV      868.4mV
[Rising Waveform]
R_fixture= 50.000
V_fixture= 1.800
V_fixture_min= 1.750
V_fixture_max= 1.850
|time   V(typ)   V(min)   V(max)
0s        1.153V     1.248V     1.043V
365ps     1.153V     1.249V     1.044V
458ps     1.16V      1.249V     1.574V
503ps     1.368V     1.249V     1.688V
569ps     1.605V     1.261V     1.77V
606ps     1.668V     1.374V     1.795V
679ps     1.734V     1.575V     1.821V
795ps     1.774V     1.686V     1.838V
1.363ns   1.799V     1.748V     1.85V
10ns      1.8V       1.75V      1.85V
[Falling Waveform]
R_fixture= 50.000
V_fixture= 1.800
V_fixture_min= 1.750
V_fixture_max= 1.850
|time   V(typ)   V(min)   V(max)
0s        1.8V       1.75V      1.85V
383ps     1.8V       1.75V      1.849V
423ps     1.8V       1.75V      1.755V
489ps     1.786V     1.75V      1.52V
561ps     1.614V     1.751V     1.341V
638ps     1.435V     1.686V     1.236V
749ps     1.301V     1.489V     1.167V
849ps     1.244V     1.385V     1.123V
1.189ns   1.177V     1.28V      1.061V
10ns      1.153V     1.248V     1.043V
[Falling Waveform]
R_fixture= 50.000
V_fixture= 0.0
V_fixture_min= 0.0
V_fixture_max= 0.0
|time   V(typ)   V(min)   V(max)
0s        683.5mV    514.1mV    868.5mV
379ps     683.3mV    514mV      866mV
415ps     683.2mV    514mV      748.3mV
474ps     678.2mV    513.9mV    340.4mV
525ps     526.6mV    514.3mV    184.5mV
621ps     165.3mV    453.7mV    75.6mV
714ps     71.69mV    185.6mV    29.75mV
832ps     24.5mV     66.72mV    8.971mV
1.312ns   442.1uV    1.7mV      127.8uV
10ns      13.92uV    26.66uV    8.279uV
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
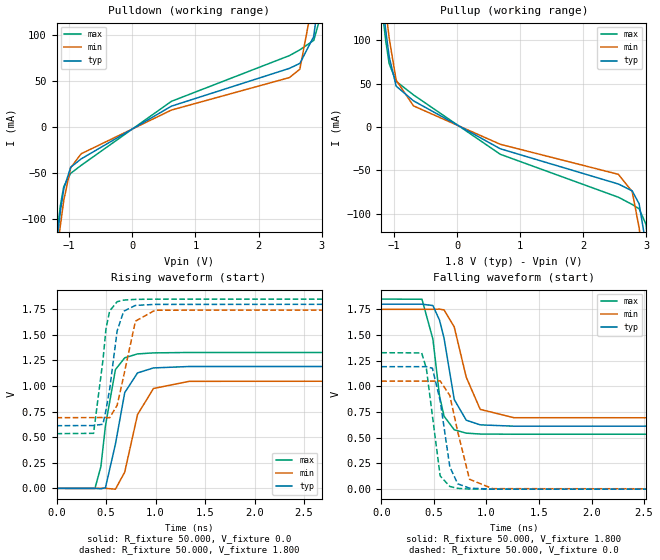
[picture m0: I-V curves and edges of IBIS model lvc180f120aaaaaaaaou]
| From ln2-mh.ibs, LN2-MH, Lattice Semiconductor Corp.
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|   Model lvc180f120aaaaaaaaou
[Model] lvc180f120aaaaaaaaou
Model_type Output
Polarity   Non-Inverting
Enable   Active-High
Vmeas =  0.900V
Cref =  0.0F
Rref =  1.000M
Vref =  0.0V
C_comp   5.000pF   4.000pF   5.500pF
[Temperature Range]   25.000   0.125k   -40.000
[Voltage Range]   1.800V   1.750V   1.850V
[C Comp Corner]
C_comp   5.000pF   4.000pF   5.500pF
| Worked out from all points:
|   slope of the pulldown table from 0 to 0.27 V, typ, clamps not added: 25.1 ohm
|   slope of the pullup table from 0 to 0.27 V, typ, clamps not added: 25 ohm
|   rising waveform, R_fixture 50.000, V_fixture 0.0: 20-80 % time 130ps typ, 162ps min, 106ps max; typ from 0 V to 1.19 V
|   rising waveform, R_fixture 50.000, V_fixture 1.800: 20-80 % time 102ps typ, 125ps min, 84.1ps max; typ from 0.613 V to 1.8 V
|   falling waveform, R_fixture 50.000, V_fixture 1.800: 20-80 % time 124ps typ, 152ps min, 105ps max; typ from 1.8 V to 0.613 V
|   falling waveform, R_fixture 50.000, V_fixture 0.0: 20-80 % time 102ps typ, 125ps min, 87.4ps max; typ from 1.19 V to 0 V
[Pulldown]
|Voltage   I(typ)   I(min)   I(max)
-1.8V     -597.4mA   -605mA     -594.1mA
-1.195V   -124.3mA   -140.2mA   -116.7mA
-1.14V    -92.18mA   -107.5mA   -85.71mA
-1.085V   -67mA      -79.52mA   -64.48mA
-975mV    -43.55mA   -44.03mA   -50.17mA
-810mV    -34.53mA   -28.96mA   -41.56mA
620mV     22.81mA    18.57mA    28.06mA
2.49V     63.9mA     53.9mA     77.77mA
2.655V    69.3mA     62.98mA    84.07mA
2.875V    98.55mA    142.6mA    94.32mA
2.985V    158.3mA    216.8mA    121mA
3.6V      672mA      732.9mA    618.7mA
[Pullup]
|Voltage   I(typ)   I(min)   I(max)
-1.8V     668.3mA    685.3mA    659.4mA
-1.185V   148.6mA    173.6mA    135mA
-1.13V    111.9mA    136.2mA    99.7mA
-1.075V   81.27mA    102.7mA    73.25mA
-965mV    47.35mA    54.25mA    52.81mA
-690mV    30.35mA    24.54mA    37.19mA
685mV     -24.95mA   -19.79mA   -31.31mA
2.555V    -65.6mA    -54.43mA   -80.83mA
2.775V    -73.58mA   -74.31mA   -89.23mA
2.885V    -88.52mA   -116.2mA   -94.25mA
2.995V    -136.9mA   -181.1mA   -112.4mA
3.6V      -603.6mA   -651.1mA   -560.2mA
[Ramp]
| variable   typ   min   max
dV/dt_r   0.715/0.130n   0.631/0.162n   0.797/0.106n
dV/dt_f   0.712/0.124n   0.635/0.152n   0.789/0.105n
R_load = 50.000
[Rising Waveform]
R_fixture= 50.000
V_fixture= 0.0
V_fixture_min= 0.0
V_fixture_max= 0.0
|time   V(typ)   V(min)   V(max)
0s        238.6nV    2.427uV    65.79nV
388ps     116.3uV    -80.63uV   -860.1uV
448ps     -4.418mV   28.73uV    212.3mV
494ps     5.531mV    187.6uV    611.4mV
595ps     432.5mV    -7.851mV   1.161V
689ps     936mV      159.2mV    1.276V
818ps     1.128V     720.3mV    1.314V
979ps     1.177V     976mV      1.324V
1.339ns   1.191V     1.046V     1.328V
10ns      1.192V     1.051V     1.328V
[Rising Waveform]
R_fixture= 50.000
V_fixture= 1.800
V_fixture_min= 1.750
V_fixture_max= 1.850
|time   V(typ)   V(min)   V(max)
0s        612.6mV    690.9mV    534.6mV
374ps     613.9mV    691.7mV    537.8mV
469ps     626.5mV    692.3mV    1.254V
500ps     767.8mV    692.3mV    1.563V
537ps     971.2mV    690.1mV    1.734V
612ps     1.537V     811.2mV    1.824V
678ps     1.731V     1.097V     1.84V
797ps     1.788V     1.634V     1.847V
996ps     1.798V     1.741V     1.849V
10ns      1.8V       1.75V      1.85V
[Falling Waveform]
R_fixture= 50.000
V_fixture= 1.800
V_fixture_min= 1.750
V_fixture_max= 1.850
|time   V(typ)   V(min)   V(max)
0s        1.8V       1.75V      1.85V
387ps     1.8V       1.75V      1.848V
491ps     1.787V     1.75V      1.46V
554ps     1.644V     1.752V     907.8mV
597ps     1.47V      1.745V     710mV
694ps     872.3mV    1.578V     577.9mV
808ps     671.1mV    1.09V      545.1mV
941ps     625.8mV    776.5mV    536.6mV
1.261ns   613.1mV    695.6mV    534.6mV
10ns      612.5mV    690.9mV    534.5mV
[Falling Waveform]
R_fixture= 50.000
V_fixture= 0.0
V_fixture_min= 0.0
V_fixture_max= 0.0
|time   V(typ)   V(min)   V(max)
0s        1.192V     1.051V     1.328V
384ps     1.192V     1.051V     1.326V
429ps     1.192V     1.051V     1.174V
486ps     1.177V     1.051V     716.3mV
560ps     862mV      1.054V     128.9mV
652ps     216.4mV    911mV      26.38mV
727ps     52.23mV    559.4mV    7.809mV
839ps     9.855mV    96.43mV    1.185mV
1.059ns   445.8uV    4.88mV     73.52uV
10ns      2.725uV    7.433uV    1.232uV
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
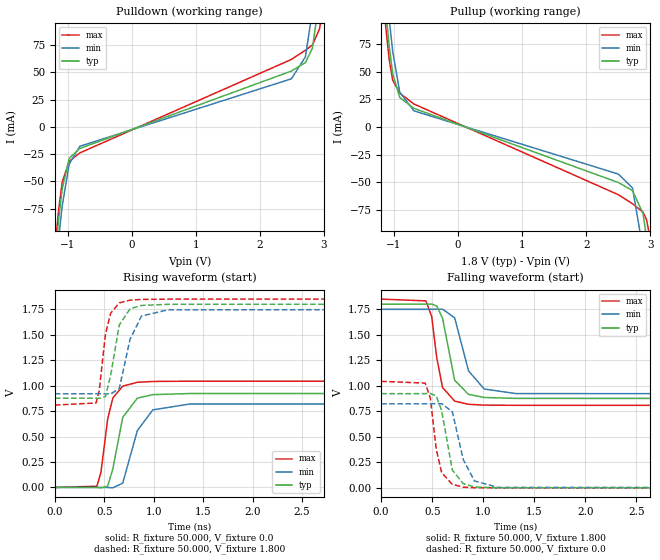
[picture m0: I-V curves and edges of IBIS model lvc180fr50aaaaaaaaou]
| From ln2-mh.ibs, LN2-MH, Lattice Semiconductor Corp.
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|   Model lvc180fr50aaaaaaaaou
[Model] lvc180fr50aaaaaaaaou
Model_type Output
Polarity   Non-Inverting
Enable   Active-High
Vmeas =  0.900V
Cref =  0.0F
Rref =  1.000M
Vref =  0.0V
C_comp   5.000pF   4.000pF   5.500pF
[Temperature Range]   25.000   0.125k   -40.000
[Voltage Range]   1.800V   1.750V   1.850V
[C Comp Corner]
C_comp   5.000pF   4.000pF   5.500pF
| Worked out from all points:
|   slope of the pulldown table from 0 to 0.27 V, typ, clamps not added: 49.2 ohm
|   slope of the pullup table from 0 to 0.27 V, typ, clamps not added: 49.2 ohm
|   rising waveform, R_fixture 50.000, V_fixture 0.0: 20-80 % time 118ps typ, 152ps min, 95.2ps max; typ from 0 V to 0.923 V
|   rising waveform, R_fixture 50.000, V_fixture 1.800: 20-80 % time 99.6ps typ, 120ps min, 83.1ps max; typ from 0.877 V to 1.8 V
|   falling waveform, R_fixture 50.000, V_fixture 1.800: 20-80 % time 104ps typ, 131ps min, 87.9ps max; typ from 1.8 V to 0.877 V
|   falling waveform, R_fixture 50.000, V_fixture 0.0: 20-80 % time 97.3ps typ, 117ps min, 83.7ps max; typ from 0.923 V to 0 V
[Pulldown]
|Voltage   I(typ)   I(min)   I(max)
-1.8V     -596mA     -603.6mA   -592.5mA
-1.195V   -118.6mA   -135.8mA   -109.7mA
-1.14V    -84.81mA   -102.1mA   -76.16mA
-1.085V   -57.12mA   -72.8mA    -50.75mA
-975mV    -28.76mA   -34.06mA   -31.57mA
-810mV    -19.75mA   -17.75mA   -23.83mA
2.49V     51.18mA    44.08mA    61.82mA
2.71V     59.04mA    64.25mA    70.37mA
2.82V     72.29mA    107.1mA    75.18mA
2.93V     119mA      174.8mA    89.91mA
2.985V    154.1mA    214.1mA    112.6mA
3.6V      670.6mA    731.8mA    617mA
[Pullup]
|Voltage   I(typ)   I(min)   I(max)
-1.8V     667.2mA    684.4mA    658mA
-1.13V    106mA      132.1mA    91.59mA
-1.075V   73.12mA    97.61mA    61.16mA
-1.02V    48.26mA    68.32mA    42.26mA
-910mV    26.56mA    31.42mA    30.55mA
-690mV    16.86mA    14.58mA    20.78mA
2.5V      -50.34mA   -42.68mA   -61.37mA
2.72V     -57.55mA   -55.2mA    -69.5mA
2.885V    -78.55mA   -111.1mA   -77.19mA
2.94V     -100.9mA   -142.4mA   -84.11mA
2.995V    -131.1mA   -177.5mA   -101.1mA
3.6V      -601.3mA   -649.3mA   -557.2mA
[Ramp]
| variable   typ   min   max
dV/dt_r   0.554/0.118n   0.494/0.152n   0.627/95.129p
dV/dt_f   0.554/0.105n   0.498/0.131n   0.625/88.091p
R_load = 50.000
[Rising Waveform]
R_fixture= 50.000
V_fixture= 0.0
V_fixture_min= 0.0
V_fixture_max= 0.0
|time   V(typ)   V(min)   V(max)
0s        369.3nV    3.503uV    105.9nV
426ps     -146.4uV   -55.87uV   11.72mV
467ps     -4.11mV    63.69uV    150.3mV
535ps     12.58mV    -554.8uV   673.7mV
587ps     183mV      -4.269mV   879.1mV
687ps     688.3mV    42.43mV    995mV
835ps     877.5mV    558.5mV    1.033V
991ps     911.6mV    761.9mV    1.041V
1.361ns   922.4mV    819.1mV    1.044V
10ns      923.2mV    823.7mV    1.044V
[Rising Waveform]
R_fixture= 50.000
V_fixture= 1.800
V_fixture_min= 1.750
V_fixture_max= 1.850
|time   V(typ)   V(min)   V(max)
0s        876.6mV    920.2mV    809mV
417ps     876.9mV    920.3mV    829.4mV
449ps     874.5mV    920.4mV    948mV
512ps     892.9mV    920.5mV    1.505V
564ps     1.096V     918.1mV    1.71V
652ps     1.596V     971mV      1.813V
761ps     1.756V     1.456V     1.84V
877ps     1.788V     1.684V     1.847V
1.145ns   1.799V     1.745V     1.85V
10ns      1.8V       1.75V      1.85V
[Falling Waveform]
R_fixture= 50.000
V_fixture= 1.800
V_fixture_min= 1.750
V_fixture_max= 1.850
|time   V(typ)   V(min)   V(max)
0s        1.8V       1.75V      1.85V
438ps     1.801V     1.75V      1.833V
495ps     1.802V     1.75V      1.679V
544ps     1.783V     1.751V     1.279V
601ps     1.665V     1.752V     984.1mV
720ps     1.054V     1.667V     850.5mV
856ps     916.5mV    1.146V     818.9mV
1.01ns    885.7mV    968.5mV    810.9mV
1.319ns   877.1mV    924.3mV    809.1mV
10ns      876.6mV    920.2mV    809mV
[Falling Waveform]
R_fixture= 50.000
V_fixture= 0.0
V_fixture_min= 0.0
V_fixture_max= 0.0
|time   V(typ)   V(min)   V(max)
0s        923.2mV    823.7mV    1.044V
431ps     923.6mV    823.6mV    1.027V
481ps     925.4mV    823.7mV    883.6mV
540ps     900.6mV    824.5mV    375.9mV
593ps     754.1mV    825.3mV    148mV
697ps     174.3mV    746.6mV    34.24mV
804ps     41.52mV    277.3mV    6.794mV
914ps     9.369mV    68.02mV    1.335mV
1.144ns   533uV      4.476mV    93.32uV
10ns      4.655uV    10.99uV    2.208uV
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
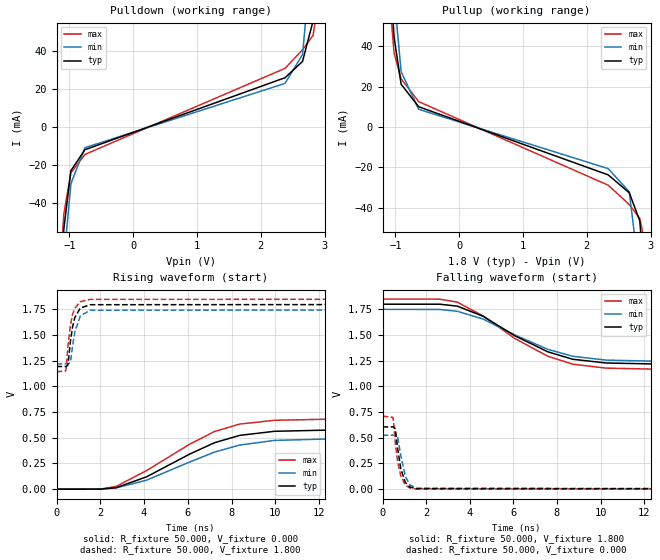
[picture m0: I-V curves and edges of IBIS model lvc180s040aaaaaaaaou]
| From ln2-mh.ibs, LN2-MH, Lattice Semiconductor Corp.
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|   Model lvc180s040aaaaaaaaou
[Model] lvc180s040aaaaaaaaou
Model_type Output
Polarity   Non-Inverting
Enable   Active-High
Vmeas =  0.900V
Cref =  0.0F
Rref =  1.000M
Vref =  0.0V
C_comp   5.000pF   4.000pF   5.500pF
[Temperature Range]   25.000   0.125k   -40.000
[Voltage Range]   1.800V   1.750V   1.850V
[C Comp Corner]
C_comp   5.000pF   4.000pF   5.500pF
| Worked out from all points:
|   slope of the pulldown table from 0 to 0.27 V, typ, clamps not added: 97.6 ohm
|   slope of the pullup table from 0 to 0.27 V, typ, clamps not added: 97.7 ohm
|   rising waveform, R_fixture 50.000, V_fixture 0.000: 20-80 % time 3.52ns typ, 3.83ns min, 3.47ns max; typ from 0 V to 0.606 V
|   rising waveform, R_fixture 50.000, V_fixture 1.800: 20-80 % time 274ps typ, 285ps min, 265ps max; typ from 1.19 V to 1.8 V
|   falling waveform, R_fixture 50.000, V_fixture 1.800: 20-80 % time 3.2ns typ, 3.35ns min, 3.22ns max; typ from 1.8 V to 1.19 V
|   falling waveform, R_fixture 50.000, V_fixture 0.000: 20-80 % time 288ps typ, 300ps min, 280ps max; typ from 0.606 V to 0 V
[Pulldown]
|Voltage   I(typ)   I(min)   I(max)
-1.8V     -594.9mA   -602.6mA   -591.2mA
-1.195V   -116.2mA   -133.8mA   -106.9mA
-1.14V    -81.89mA   -99.71mA   -72.47mA
-1.085V   -53.29mA   -69.9mA    -45.55mA
-975mV    -22.88mA   -29.74mA   -23.99mA
-755mV    -11.87mA   -10.81mA   -14.34mA
2.38V     25.94mA    22.97mA    30.86mA
2.655V    34.5mA     38.12mA    40.62mA
2.82V     55.71mA    98.51mA    48.22mA
2.93V     109.9mA    169.2mA    71.45mA
2.985V    147.2mA    209.4mA    100.1mA
3.6V      668.3mA    729.8mA    614.2mA
[Pullup]
|Voltage   I(typ)   I(min)   I(max)
-1.8V     666.6mA    683.8mA    657.3mA
-1.13V    103.9mA    130.4mA    88.94mA
-1.075V   70.36mA    95.55mA    57.33mA
-1.02V    44.5mA     65.73mA    36.8mA
-910mV    21.26mA    27.55mA    23.96mA
-635mV    10.12mA    8.855mA    12.65mA
2.335V    -23.67mA   -20.57mA   -28.79mA
2.665V    -32.52mA   -32.05mA   -38.34mA
2.83V     -46.45mA   -74.63mA   -45.25mA
2.94V     -89.38mA   -135.4mA   -61.6mA
2.995V    -122.2mA   -171.5mA   -85.2mA
3.6V      -597.5mA   -646.3mA   -552.4mA
[Ramp]
| variable   typ   min   max
dV/dt_r   0.371/3.527n   0.322/3.838n   0.435/3.468n
dV/dt_f   0.371/3.197n   0.325/3.351n   0.433/3.220n
R_load = 50.000
[Rising Waveform]
R_fixture = 50.000
V_fixture = 0.000
V_fixture_min = 0.000
V_fixture_max = 0.000
|  time   V(typ)   V(min)   V(max)
0s        1.802uV    8.512uV    279.8nV
2.005ns   342.7uV    684.9uV    892.5uV
2.725ns   14.36mV    12.78mV    26.73mV
4.119ns   120.5mV    87.8mV     181.4mV
6.064ns   339.1mV    262.6mV    435.1mV
7.219ns   452mV      361mV      560.9mV
8.375ns   523.5mV    429.8mV    633.6mV
9.955ns   563.1mV    474.3mV    670.2mV
18.4ns    604.2mV    523.8mV    707.8mV
50ns      605.8mV    525.3mV    710.2mV
[Rising Waveform]
R_fixture = 50.000
V_fixture = 1.800
V_fixture_min = 1.750
V_fixture_max = 1.850
|  time   V(typ)   V(min)   V(max)
0s        1.194V     1.22V      1.142V
420ps     1.194V     1.22V      1.151V
446ps     1.193V     1.22V      1.186V
522ps     1.21V      1.22V      1.395V
636ps     1.441V     1.235V     1.595V
733ps     1.579V     1.393V     1.699V
831ps     1.667V     1.527V     1.76V
1.084ns   1.762V     1.685V     1.824V
1.531ns   1.795V     1.741V     1.847V
50ns      1.8V       1.75V      1.85V
[Falling Waveform]
R_fixture = 50.000
V_fixture = 1.800
V_fixture_min = 1.750
V_fixture_max = 1.850
|  time   V(typ)   V(min)   V(max)
0s        1.8V       1.75V      1.85V
2.62ns    1.8V       1.749V     1.849V
3.429ns   1.781V     1.731V     1.82V
4.615ns   1.682V     1.655V     1.685V
6.055ns   1.494V     1.502V     1.468V
7.574ns   1.337V     1.361V     1.294V
8.726ns   1.264V     1.293V     1.216V
10.25ns   1.228V     1.256V     1.178V
17.6ns    1.195V     1.221V     1.145V
50ns      1.194V     1.22V      1.142V
[Falling Waveform]
R_fixture = 50.000
V_fixture = 0.000
V_fixture_min = 0.000
V_fixture_max = 0.000
|  time   V(typ)   V(min)   V(max)
0s        605.8mV    525.3mV    710.2mV
469ps     606mV      525.3mV    698.7mV
509ps     606.3mV    525.3mV    647.1mV
586ps     584.7mV    525.6mV    443.9mV
684ps     401.8mV    516.2mV    274.8mV
835ps     197.1mV    324.9mV    129.7mV
1.047ns   64.48mV    121.9mV    38.07mV
1.245ns   21.42mV    43.58mV    12.24mV
1.537ns   4.539mV    9.525mV    2.593mV
50ns      1.802uV    8.512uV    279.8nV
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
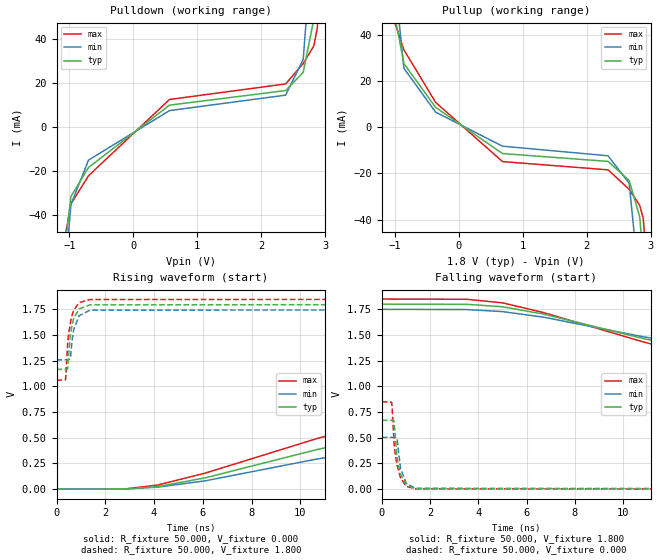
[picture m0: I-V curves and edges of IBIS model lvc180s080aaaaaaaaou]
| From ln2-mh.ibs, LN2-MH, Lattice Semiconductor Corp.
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|   Model lvc180s080aaaaaaaaou
[Model] lvc180s080aaaaaaaaou
Model_type Output
Polarity   Non-Inverting
Enable   Active-High
Vmeas =  0.900V
Cref =  0.0F
Rref =  1.000M
Vref =  0.0V
C_comp   5.000pF   4.000pF   5.500pF
[Temperature Range]   25.000   0.125k   -40.000
[Voltage Range]   1.800V   1.750V   1.850V
[C Comp Corner]
C_comp   5.000pF   4.000pF   5.500pF
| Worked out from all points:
|   slope of the pulldown table from 0 to 0.27 V, typ, clamps not added: 49.4 ohm
|   slope of the pullup table from 0 to 0.27 V, typ, clamps not added: 48.8 ohm
|   rising waveform, R_fixture 50.000, V_fixture 0.000: 20-80 % time 7.33ns typ, 7.16ns min, 7.63ns max; typ from 0 V to 0.67 V
|   rising waveform, R_fixture 50.000, V_fixture 1.800: 20-80 % time 227ps typ, 228ps min, 229ps max; typ from 1.17 V to 1.8 V
|   falling waveform, R_fixture 50.000, V_fixture 1.800: 20-80 % time 7.23ns typ, 6.98ns min, 7.57ns max; typ from 1.8 V to 1.17 V
|   falling waveform, R_fixture 50.000, V_fixture 0.000: 20-80 % time 239ps typ, 239ps min, 243ps max; typ from 0.67 V to 0 V
[Pulldown]
|Voltage   I(typ)   I(min)   I(max)
-1.8V     -595.2mA   -602.9mA   -591.4mA
-1.14V    -85.93mA   -102.5mA   -77.56mA
-1.085V   -58.79mA   -73.44mA   -52.97mA
-975mV    -31.59mA   -35.21mA   -34.99mA
-700mV    -18.35mA   -15.02mA   -22.12mA
565mV     10.01mA    7.529mA    12.59mA
2.38V     16.66mA    14.57mA    19.68mA
2.655V    24.98mA    30.9mA     28.97mA
2.82V     49.1mA     94.77mA    36.95mA
2.875V    73.68mA    128.8mA    45.22mA
2.985V    144.3mA    207.3mA    95.51mA
3.6V      667.3mA    728.9mA    613mA
[Pullup]
|Voltage   I(typ)   I(min)   I(max)
-1.8V     667mA      684.1mA    657.9mA
-1.075V   75.25mA    98.4mA     64.53mA
-1.02V    51.35mA    69.47mA    47.14mA
-855mV    27.49mA    25.43mA    33.42mA
-360mV    8.539mA    6.482mA    10.71mA
685mV     -11.42mA   -8.227mA   -14.89mA
2.335V    -14.81mA   -12.38mA   -18.45mA
2.665V    -23.05mA   -24.29mA   -26.89mA
2.83V     -38.84mA   -70.02mA   -33.87mA
2.885V    -57.42mA   -98.88mA   -39.4mA
2.995V    -118.7mA   -168.9mA   -79.65mA
3.6V      -596mA     -645mA     -550.6mA
[Ramp]
| variable   typ   min   max
dV/dt_r   0.410/7.337n   0.309/7.174n   0.521/7.637n
dV/dt_f   0.389/7.242n   0.301/6.991n   0.484/7.598n
R_load = 50.000
[Rising Waveform]
R_fixture = 50.000
V_fixture = 0.000
V_fixture_min = 0.000
V_fixture_max = 0.000
|  time   V(typ)   V(min)   V(max)
0s        53.33uV    58.88uV    48.71uV
2.836ns   1.543mV    2.245mV    3.154mV
4.149ns   24.67mV    19.6mV     40.4mV
6.093ns   110mV      80.96mV    155.8mV
10.69ns   386mV      293.9mV    493.1mV
12.84ns   495mV      376.3mV    626.8mV
15.5ns    588.6mV    445.7mV    742.8mV
18.74ns   652.6mV    492.7mV    821.5mV
22.46ns   669.5mV    503.5mV    850.4mV
50ns      670.1mV    504mV      851.3mV
[Rising Waveform]
R_fixture = 50.000
V_fixture = 1.800
V_fixture_min = 1.750
V_fixture_max = 1.850
|  time   V(typ)   V(min)   V(max)
0s        1.165V     1.258V     1.059V
372ps     1.166V     1.259V     1.066V
455ps     1.17V      1.259V     1.411V
494ps     1.292V     1.259V     1.503V
569ps     1.502V     1.27V      1.621V
642ps     1.605V     1.455V     1.698V
707ps     1.663V     1.555V     1.743V
928ps     1.755V     1.689V     1.815V
1.378ns   1.794V     1.742V     1.846V
50ns      1.8V       1.75V      1.85V
[Falling Waveform]
R_fixture = 50.000
V_fixture = 1.800
V_fixture_min = 1.750
V_fixture_max = 1.850
|  time   V(typ)   V(min)   V(max)
0s        1.8V       1.75V      1.85V
3.509ns   1.799V     1.748V     1.848V
5.003ns   1.775V     1.728V     1.813V
6.693ns   1.704V     1.674V     1.719V
10.83ns   1.466V     1.483V     1.433V
13.64ns   1.326V     1.374V     1.267V
16.48ns   1.231V     1.303V     1.149V
19.37ns   1.181V     1.268V     1.084V
23.06ns   1.166V     1.259V     1.06V
50ns      1.165V     1.258V     1.059V
[Falling Waveform]
R_fixture = 50.000
V_fixture = 0.000
V_fixture_min = 0.000
V_fixture_max = 0.000
|  time   V(typ)   V(min)   V(max)
0s        670.1mV    504mV      851.3mV
406ps     669.7mV    503.9mV    845.7mV
429ps     669.8mV    503.8mV    792.8mV
502ps     664.8mV    503.6mV    464.3mV
545ps     556.1mV    504.1mV    360.8mV
630ps     306.9mV    487.3mV    234mV
777ps     142.6mV    199.8mV    107.9mV
1.012ns   38.7mV     58.22mV    27.56mV
1.392ns   4.903mV    7.961mV    3.292mV
50ns      53.33uV    58.88uV    48.71uV
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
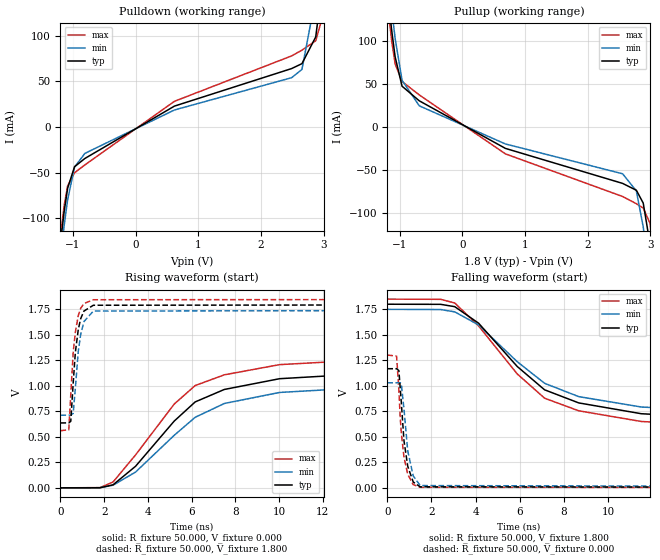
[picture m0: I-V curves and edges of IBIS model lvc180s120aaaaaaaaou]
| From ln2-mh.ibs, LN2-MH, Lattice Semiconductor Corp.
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|   Model lvc180s120aaaaaaaaou
[Model] lvc180s120aaaaaaaaou
Model_type Output
Polarity   Non-Inverting
Enable   Active-High
Vmeas =  0.900V
Cref =  0.0F
Rref =  1.000M
Vref =  0.0V
C_comp   5.000pF   4.000pF   5.500pF
[Temperature Range]   25.000   0.125k   -40.000
[Voltage Range]   1.800V   1.750V   1.850V
[C Comp Corner]
C_comp   5.000pF   4.000pF   5.500pF
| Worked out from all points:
|   slope of the pulldown table from 0 to 0.27 V, typ, clamps not added: 25.1 ohm
|   slope of the pullup table from 0 to 0.27 V, typ, clamps not added: 25 ohm
|   rising waveform, R_fixture 50.000, V_fixture 0.000: 20-80 % time 3.53ns typ, 3.75ns min, 3.3ns max; typ from 0 V to 1.17 V
|   rising waveform, R_fixture 50.000, V_fixture 1.800: 20-80 % time 285ps typ, 299ps min, 274ps max; typ from 0.636 V to 1.8 V
|   falling waveform, R_fixture 50.000, V_fixture 1.800: 20-80 % time 3.75ns typ, 3.82ns min, 3.58ns max; typ from 1.8 V to 0.636 V
|   falling waveform, R_fixture 50.000, V_fixture 0.000: 20-80 % time 301ps typ, 320ps min, 286ps max; typ from 1.17 V to 0 V
[Pulldown]
|Voltage   I(typ)   I(min)   I(max)
-1.8V     -597.4mA   -605mA     -594.1mA
-1.195V   -124.3mA   -140.2mA   -116.7mA
-1.14V    -92.18mA   -107.5mA   -85.71mA
-1.085V   -67mA      -79.52mA   -64.48mA
-975mV    -43.55mA   -44.03mA   -50.17mA
-810mV    -34.53mA   -28.96mA   -41.56mA
620mV     22.81mA    18.57mA    28.06mA
2.49V     63.9mA     53.9mA     77.77mA
2.655V    69.3mA     62.98mA    84.07mA
2.875V    98.55mA    142.6mA    94.32mA
2.985V    158.3mA    216.8mA    121mA
3.6V      672mA      732.9mA    618.7mA
[Pullup]
|Voltage   I(typ)   I(min)   I(max)
-1.8V     668.3mA    685.3mA    659.4mA
-1.185V   148.6mA    173.6mA    135mA
-1.13V    111.9mA    136.2mA    99.7mA
-1.075V   81.27mA    102.7mA    73.25mA
-965mV    47.35mA    54.25mA    52.81mA
-690mV    30.35mA    24.54mA    37.19mA
685mV     -24.95mA   -19.79mA   -31.31mA
2.555V    -65.6mA    -54.43mA   -80.83mA
2.775V    -73.58mA   -74.31mA   -89.23mA
2.885V    -88.52mA   -116.2mA   -94.25mA
2.995V    -136.9mA   -181.1mA   -112.4mA
3.6V      -603.6mA   -651.1mA   -560.2mA
[Ramp]
| variable   typ   min   max
dV/dt_r   0.715/3.533n   0.631/3.748n   0.797/3.304n
dV/dt_f   0.712/3.746n   0.635/3.827n   0.789/3.584n
R_load = 50.000
[Rising Waveform]
R_fixture = 50.000
V_fixture = 0.000
V_fixture_min = 0.000
V_fixture_max = 0.000
|  time   V(typ)   V(min)   V(max)
0s        34.46uV    36.61uV    30.69uV
1.806ns   849.7uV    1.313mV    2.539mV
2.406ns   29.58mV    26.04mV    57.12mV
3.438ns   211.8mV    154.9mV    323.2mV
5.206ns   654.6mV    515.3mV    821.4mV
6.166ns   842.5mV    691.8mV    1.003V
7.498ns   964.5mV    827mV      1.108V
10.03ns   1.07V      935.3mV    1.208V
17.65ns   1.165V     1.028V     1.297V
50ns      1.168V     1.03V      1.302V
[Rising Waveform]
R_fixture = 50.000
V_fixture = 1.800
V_fixture_min = 1.750
V_fixture_max = 1.850
|  time   V(typ)   V(min)   V(max)
0s        636.1mV    711.9mV    560.4mV
381ps     637.1mV    712.5mV    569.1mV
472ps     652.2mV    713mV      908mV
583ps     1.026V     730.5mV    1.327V
682ps     1.328V     976.6mV    1.527V
815ps     1.551V     1.337V     1.689V
925ps     1.658V     1.503V     1.759V
1.075ns   1.733V     1.63V      1.807V
1.505ns   1.79V      1.733V     1.844V
50ns      1.8V       1.75V      1.85V
[Falling Waveform]
R_fixture = 50.000
V_fixture = 1.800
V_fixture_min = 1.750
V_fixture_max = 1.850
|  time   V(typ)   V(min)   V(max)
0s        1.8V       1.75V      1.85V
2.418ns   1.799V     1.748V     1.848V
3.058ns   1.776V     1.725V     1.812V
4.138ns   1.614V     1.597V     1.587V
5.888ns   1.19V      1.237V     1.117V
7.129ns   961.1mV    1.025V     878.9mV
8.678ns   832.7mV    894.3mV    755.4mV
11.52ns   726.6mV    792.3mV    650.5mV
19.41ns   638.5mV    713.9mV    563.9mV
50ns      636.1mV    711.9mV    560.4mV
[Falling Waveform]
R_fixture = 50.000
V_fixture = 0.000
V_fixture_min = 0.000
V_fixture_max = 0.000
|  time   V(typ)   V(min)   V(max)
0s        1.168V     1.03V      1.302V
420ps     1.168V     1.03V      1.291V
524ps     1.149V     1.03V      956.9mV
579ps     993mV      1.031V     711.9mV
632ps     843.8mV    1.021V     542.3mV
754ps     464.1mV    774mV      304mV
925ps     211.8mV    362.3mV    132.9mV
1.175ns   57.05mV    116.5mV    31.43mV
1.491ns   10.36mV    22.4mV     5.766mV
50ns      34.46uV    36.61uV    30.69uV
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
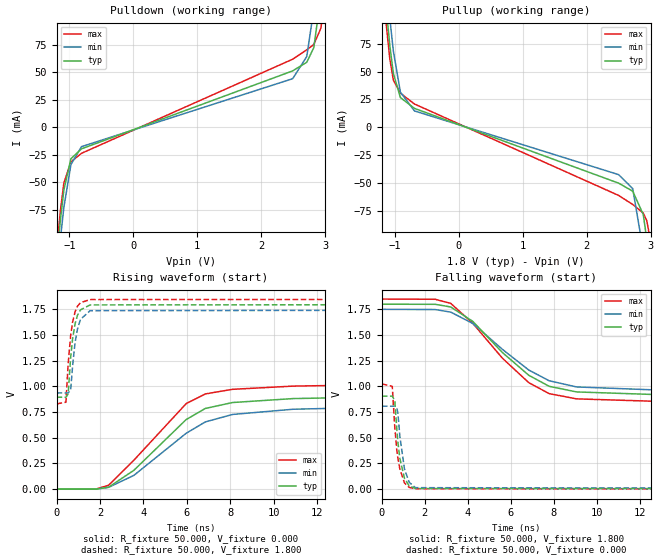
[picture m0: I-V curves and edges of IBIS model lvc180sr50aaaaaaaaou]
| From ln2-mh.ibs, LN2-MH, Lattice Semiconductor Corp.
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|   Model lvc180sr50aaaaaaaaou
[Model] lvc180sr50aaaaaaaaou
Model_type Output
Polarity   Non-Inverting
Enable   Active-High
Vmeas =  0.900V
Cref =  0.0F
Rref =  1.000M
Vref =  0.0V
C_comp   5.000pF   4.000pF   5.500pF
[Temperature Range]   25.000   0.125k   -40.000
[Voltage Range]   1.800V   1.750V   1.850V
[C Comp Corner]
C_comp   5.000pF   4.000pF   5.500pF
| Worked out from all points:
|   slope of the pulldown table from 0 to 0.27 V, typ, clamps not added: 49.2 ohm
|   slope of the pullup table from 0 to 0.27 V, typ, clamps not added: 49.2 ohm
|   rising waveform, R_fixture 50.000, V_fixture 0.000: 20-80 % time 2.73ns typ, 3.02ns min, 2.62ns max; typ from 0 V to 0.905 V
|   rising waveform, R_fixture 50.000, V_fixture 1.800: 20-80 % time 281ps typ, 292ps min, 273ps max; typ from 0.895 V to 1.8 V
|   falling waveform, R_fixture 50.000, V_fixture 1.800: 20-80 % time 2.76ns typ, 2.92ns min, 2.75ns max; typ from 1.8 V to 0.895 V
|   falling waveform, R_fixture 50.000, V_fixture 0.000: 20-80 % time 295ps typ, 308ps min, 285ps max; typ from 0.905 V to 0 V
[Pulldown]
|Voltage   I(typ)   I(min)   I(max)
-1.8V     -596mA     -603.6mA   -592.5mA
-1.195V   -118.6mA   -135.8mA   -109.7mA
-1.14V    -84.81mA   -102.1mA   -76.16mA
-1.085V   -57.12mA   -72.8mA    -50.75mA
-975mV    -28.76mA   -34.06mA   -31.57mA
-810mV    -19.75mA   -17.75mA   -23.83mA
2.49V     51.18mA    44.08mA    61.82mA
2.71V     59.04mA    64.25mA    70.37mA
2.82V     72.29mA    107.1mA    75.18mA
2.93V     119mA      174.8mA    89.91mA
2.985V    154.1mA    214.1mA    112.6mA
3.6V      670.6mA    731.8mA    617mA
[Pullup]
|Voltage   I(typ)   I(min)   I(max)
-1.8V     667.2mA    684.4mA    658mA
-1.13V    106mA      132.1mA    91.59mA
-1.075V   73.12mA    97.61mA    61.16mA
-1.02V    48.26mA    68.32mA    42.26mA
-910mV    26.56mA    31.42mA    30.55mA
-690mV    16.86mA    14.58mA    20.78mA
2.5V      -50.34mA   -42.68mA   -61.37mA
2.72V     -57.55mA   -55.19mA   -69.5mA
2.885V    -78.55mA   -111.1mA   -77.19mA
2.94V     -100.9mA   -142.4mA   -84.11mA
2.995V    -131.1mA   -177.5mA   -101.1mA
3.6V      -601.3mA   -649.3mA   -557.2mA
[Ramp]
| variable   typ   min   max
dV/dt_r   0.554/2.733n   0.494/3.024n   0.627/2.625n
dV/dt_f   0.554/2.772n   0.498/2.932n   0.625/2.760n
R_load = 50.000
[Rising Waveform]
R_fixture = 50.000
V_fixture = 0.000
V_fixture_min = 0.000
V_fixture_max = 0.000
|  time   V(typ)   V(min)   V(max)
0s        2.476uV    4.84uV     1.626uV
1.828ns   572.4uV    930.9uV    1.802mV
2.396ns   19.14mV    17.74mV    38mV
3.561ns   183.3mV    134.1mV    281.6mV
5.968ns   677.2mV    543.8mV    832.1mV
6.85ns    785.2mV    654.4mV    926.6mV
8.101ns   843.1mV    727mV      971.7mV
10.9ns    881.6mV    777.9mV    1.003V
16.37ns   902.8mV    805.1mV    1.021V
50ns      905.1mV    807.5mV    1.024V
[Rising Waveform]
R_fixture = 50.000
V_fixture = 1.800
V_fixture_min = 1.750
V_fixture_max = 1.850
|  time   V(typ)   V(min)   V(max)
0s        894.7mV    936.5mV    829.4mV
433ps     894.3mV    936.6mV    846.4mV
535ps     926.7mV    936.1mV    1.22V
651ps     1.285V     966.8mV    1.496V
743ps     1.469V     1.205V     1.628V
850ps     1.606V     1.421V     1.724V
963ps     1.691V     1.557V     1.78V
1.102ns   1.745V     1.652V     1.815V
1.547ns   1.793V     1.737V     1.845V
50ns      1.8V       1.75V      1.85V
[Falling Waveform]
R_fixture = 50.000
V_fixture = 1.800
V_fixture_min = 1.750
V_fixture_max = 1.850
|  time   V(typ)   V(min)   V(max)
0s        1.8V       1.75V      1.85V
2.479ns   1.799V     1.748V     1.848V
3.203ns   1.773V     1.723V     1.808V
4.233ns   1.632V     1.612V     1.613V
5.603ns   1.33V      1.361V     1.275V
6.834ns   1.108V     1.159V     1.036V
7.779ns   1.001V     1.055V     929.7mV
9.053ns   946.2mV    994.8mV    878.8mV
16.01ns   897.9mV    939.4mV    833.6mV
50ns      894.7mV    936.5mV    829.4mV
[Falling Waveform]
R_fixture = 50.000
V_fixture = 0.000
V_fixture_min = 0.000
V_fixture_max = 0.000
|  time   V(typ)   V(min)   V(max)
0s        905.1mV    807.5mV    1.024V
484ps     905.7mV    807.5mV    1.001V
604ps     860.3mV    808.3mV    597.2mV
694ps     590.4mV    792.5mV    384.2mV
746ps     458.7mV    739.8mV    301.3mV
839ps     297.8mV    512.9mV    195.2mV
1.051ns   106.6mV    196.6mV    60.62mV
1.271ns   31.33mV    66.87mV    17.15mV
1.562ns   6.726mV    14.59mV    3.791mV
50ns      2.476uV    4.84uV     1.626uV
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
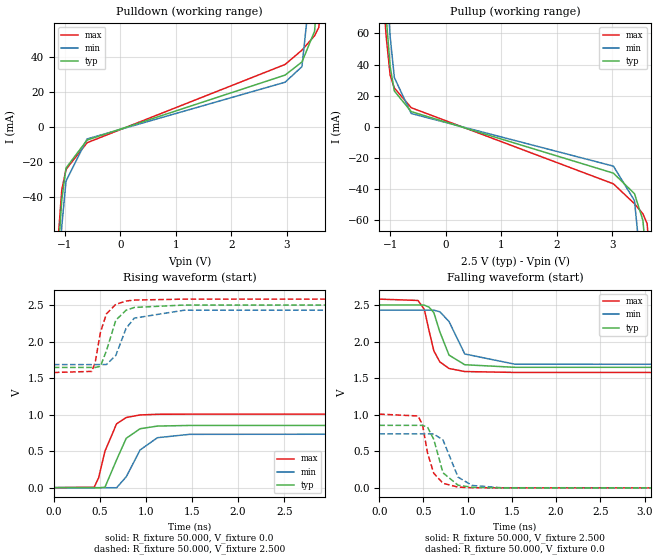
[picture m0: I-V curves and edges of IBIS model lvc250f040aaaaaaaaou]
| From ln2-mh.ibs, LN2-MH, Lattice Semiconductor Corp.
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|   Model lvc250f040aaaaaaaaou
[Model] lvc250f040aaaaaaaaou
Model_type Output
Polarity   Non-Inverting
Enable   Active-High
Vmeas =  1.250V
Cref =  0.0F
Rref =  1.000M
Vref =  0.0V
C_comp   5.000pF   4.000pF   5.500pF
[Temperature Range]   25.000   0.125k   -40.000
[Voltage Range]   2.500V   2.430V   2.580V
[C Comp Corner]
C_comp   5.000pF   4.000pF   5.500pF
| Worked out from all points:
|   slope of the pulldown table from 0 to 0.375 V, typ, clamps not added: 97.7 ohm
|   slope of the pullup table from 0 to 0.375 V, typ, clamps not added: 97.8 ohm
|   rising waveform, R_fixture 50.000, V_fixture 0.0: 20-80 % time 164ps typ, 202ps min, 140ps max; typ from 0 V to 0.853 V
|   rising waveform, R_fixture 50.000, V_fixture 2.500: 20-80 % time 133ps typ, 158ps min, 113ps max; typ from 1.65 V to 2.5 V
|   falling waveform, R_fixture 50.000, V_fixture 2.500: 20-80 % time 148ps typ, 178ps min, 129ps max; typ from 2.5 V to 1.65 V
|   falling waveform, R_fixture 50.000, V_fixture 0.0: 20-80 % time 127ps typ, 144ps min, 115ps max; typ from 0.855 V to 0 V
[Pulldown]
|Voltage   I(typ)   I(min)   I(max)
-2.5V     -1.193A    -1.196A    -1.191A
-1.208V   -124.9mA   -142.3mA   -115.7mA
-1.132V   -77.28mA   -95.08mA   -67.94mA
-1.056V   -41.5mA    -56.51mA   -35.82mA
-980mV    -23.44mA   -30.89mA   -24.21mA
-600mV    -7.479mA   -6.85mA    -9.008mA
2.972V    29.56mA    25.5mA     35.62mA
3.276V    37.04mA    34.38mA    43.78mA
3.504V    54.56mA    102mA      52.02mA
3.58V     83.28mA    149.3mA    56.75mA
3.732V    182.9mA    261.6mA    112.9mA
5V        1.308A     1.384A     1.228A
[Pullup]
|Voltage   I(typ)   I(min)   I(max)
-2.5V     1.307A     1.318A     1.3A
-1.156V   121.7mA    148.3mA    106.4mA
-1.08V    73.14mA    98.56mA    59.79mA
-1.004V   38.84mA    58.25mA    33.22mA
-928mV    23.06mA    31.67mA    24.99mA
-624mV    9.842mA    8.614mA    12.33mA
3.024V    -29.66mA   -25.16mA   -36.52mA
3.404V    -42.85mA   -47.28mA   -49.27mA
3.556V    -59.94mA   -101.7mA   -55.76mA
3.632V    -89.74mA   -146.2mA   -62.01mA
3.784V    -186.1mA   -251.8mA   -124.5mA
5V        -1.197A    -1.259A    -1.126A
[Ramp]
| variable   typ   min   max
dV/dt_r   0.512/0.164n   0.441/0.202n   0.604/0.140n
dV/dt_f   0.513/0.148n   0.447/0.178n   0.602/0.129n
R_load = 50.000
[Rising Waveform]
R_fixture= 50.000
V_fixture= 0.0
V_fixture_min= 0.0
V_fixture_max= 0.0
|time   V(typ)   V(min)   V(max)
0s        1.21uV     9.054uV    329.6nV
438ps     -661.1uV   -298.5uV   6.406mV
486ps     -2.962mV   -215.8uV   133.6mV
555ps     5.792mV    -1.052mV   498.8mV
681ps     380mV      -1.349mV   874mV
786ps     675.5mV    148.2mV    959.8mV
936ps     806.1mV    515.3mV    995.1mV
1.124ns   842.7mV    683.3mV    1.004V
1.474ns   851.1mV    729.7mV    1.006V
10ns      853.4mV    735.8mV    1.007V
[Rising Waveform]
R_fixture= 50.000
V_fixture= 2.500
V_fixture_min= 2.430
V_fixture_max= 2.580
|time   V(typ)   V(min)   V(max)
0s        1.645V     1.684V     1.576V
412ps     1.645V     1.684V     1.591V
449ps     1.645V     1.684V     1.713V
506ps     1.661V     1.685V     2.127V
572ps     1.878V     1.685V     2.38V
673ps     2.292V     1.81V      2.509V
784ps     2.428V     2.179V     2.554V
873ps     2.466V     2.32V      2.567V
1.413ns   2.499V     2.428V     2.58V
10ns      2.5V       2.43V      2.58V
[Falling Waveform]
R_fixture= 50.000
V_fixture= 2.500
V_fixture_min= 2.430
V_fixture_max= 2.580
|time   V(typ)   V(min)   V(max)
0s        2.5V       2.43V      2.58V
438ps     2.5V       2.43V      2.562V
510ps     2.498V     2.43V      2.439V
563ps     2.47V      2.431V     2.149V
617ps     2.396V     2.429V     1.874V
685ps     2.132V     2.407V     1.722V
789ps     1.815V     2.274V     1.632V
967ps     1.683V     1.83V      1.59V
1.536ns   1.648V     1.69V      1.578V
10ns      1.646V     1.686V     1.577V
[Falling Waveform]
R_fixture= 50.000
V_fixture= 0.0
V_fixture_min= 0.0
V_fixture_max= 0.0
|time   V(typ)   V(min)   V(max)
0s        854.6mV    738.1mV    1.008V
438ps     854.6mV    737.9mV    982.9mV
489ps     854.2mV    737.8mV    864.8mV
546ps     830mV      738.3mV    475.7mV
616ps     663.7mV    735.9mV    200.4mV
721ps     205.4mV    654.4mV    62.23mV
891ps     36.42mV    146.6mV    10.15mV
1.051ns   7.656mV    32.9mV     1.99mV
1.38ns    413.3uV    1.789mV    169.2uV
10ns      35.4uV     36.86uV    35.97uV
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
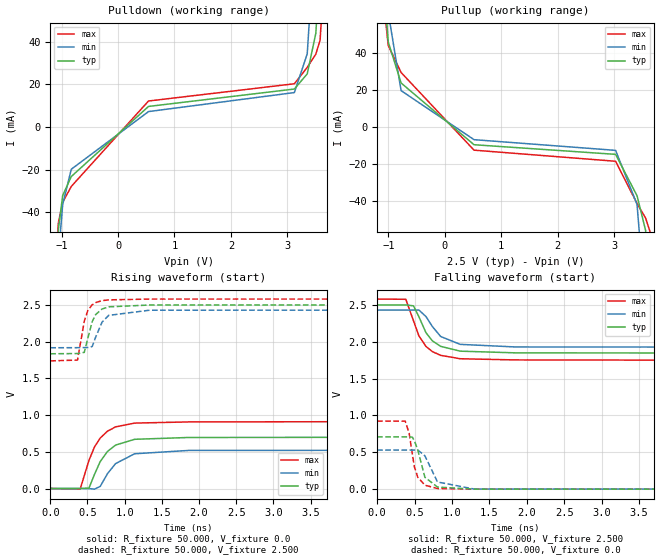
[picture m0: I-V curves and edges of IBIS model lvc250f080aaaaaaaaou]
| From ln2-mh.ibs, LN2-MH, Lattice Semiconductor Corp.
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|   Model lvc250f080aaaaaaaaou
[Model] lvc250f080aaaaaaaaou
Model_type Output
Polarity   Non-Inverting
Enable   Active-High
Vmeas =  1.250V
Cref =  0.0F
Rref =  1.000M
Vref =  0.0V
C_comp   5.000pF   4.000pF   5.500pF
[Temperature Range]   25.000   0.125k   -40.000
[Voltage Range]   2.500V   2.430V   2.580V
[C Comp Corner]
C_comp   5.000pF   4.000pF   5.500pF
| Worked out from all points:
|   slope of the pulldown table from 0 to 0.375 V, typ, clamps not added: 51.3 ohm
|   slope of the pullup table from 0 to 0.375 V, typ, clamps not added: 50.7 ohm
|   rising waveform, R_fixture 50.000, V_fixture 0.0: 20-80 % time 258ps typ, 274ps min, 250ps max; typ from 0 V to 0.702 V
|   rising waveform, R_fixture 50.000, V_fixture 2.500: 20-80 % time 121ps typ, 148ps min, 99.7ps max; typ from 1.84 V to 2.5 V
|   falling waveform, R_fixture 50.000, V_fixture 2.500: 20-80 % time 242ps typ, 259ps min, 232ps max; typ from 2.5 V to 1.84 V
|   falling waveform, R_fixture 50.000, V_fixture 0.0: 20-80 % time 118ps typ, 141ps min, 101ps max; typ from 0.71 V to 0 V
[Pulldown]
|Voltage   I(typ)   I(min)   I(max)
-2.5V     -1.193A    -1.196A    -1.19A
-1.132V   -81.49mA   -97.97mA   -73.3mA
-1.056V   -47.95mA   -60.51mA   -44.7mA
-980mV    -32.05mA   -36.26mA   -35.19mA
-828mV    -23.16mA   -19.74mA   -27.81mA
540mV     9.707mA    7.295mA    12.25mA
3.124V    17.87mA    16.21mA    20.34mA
3.352V    24.97mA    34.39mA    28.01mA
3.504V    43.96mA    97.16mA    34.24mA
3.58V     76.44mA    145.7mA    40.74mA
3.732V    179.6mA    259.3mA    106.8mA
5V        1.307A     1.383A     1.226A
[Pullup]
|Voltage   I(typ)   I(min)   I(max)
-2.5V     1.307A     1.318A     1.3A
-1.156V   124.7mA    150.2mA    110.5mA
-1.08V    77.87mA    101.3mA    66.77mA
-1.004V   46.29mA    62.28mA    44.31mA
-776mV    23.97mA    19.8mA     29.66mA
516mV     -9.544mA   -6.801mA   -12.49mA
3.024V    -14.77mA   -12.6mA    -18.52mA
3.404V    -37.24mA   -41.97mA   -41.42mA
3.556V    -56.06mA   -98.76mA   -49.36mA
3.632V    -87.15mA   -143.9mA   -56.52mA
3.784V    -184.6mA   -250.2mA   -122.2mA
5V        -1.196A    -1.258A    -1.125A
[Ramp]
| variable   typ   min   max
dV/dt_r   0.421/0.258n   0.314/0.273n   0.551/0.250n
dV/dt_f   0.395/0.242n   0.303/0.259n   0.502/0.232n
R_load = 50.000
[Rising Waveform]
R_fixture= 50.000
V_fixture= 0.0
V_fixture_min= 0.0
V_fixture_max= 0.0
|time   V(typ)   V(min)   V(max)
0s        1.135uV    9.529uV    308.8nV
402ps     -76.77uV   -315.3uV   -7.075mV
520ps     5.18mV     -409.2uV   383.5mV
594ps     191.5mV    -8.938mV   565.2mV
671ps     366.5mV    28.42mV    686.9mV
769ps     504.8mV    202mV      781.1mV
878ps     591.5mV    339.5mV    839.4mV
1.134ns   670.1mV    473.2mV    890.9mV
1.859ns   695mV      518.4mV    906.9mV
10ns      702.5mV    523.5mV    917.9mV
[Rising Waveform]
R_fixture= 50.000
V_fixture= 2.500
V_fixture_min= 2.430
V_fixture_max= 2.580
|time   V(typ)   V(min)   V(max)
0s        1.835V     1.917V     1.738V
366ps     1.838V     1.918V     1.749V
457ps     1.854V     1.92V      2.278V
504ps     2.043V     1.92V      2.424V
564ps     2.274V     1.934V     2.503V
610ps     2.369V     2.061V     2.532V
695ps     2.444V     2.264V     2.558V
785ps     2.474V     2.358V     2.569V
1.335ns   2.499V     2.428V     2.58V
10ns      2.5V       2.43V      2.58V
[Falling Waveform]
R_fixture= 50.000
V_fixture= 2.500
V_fixture_min= 2.430
V_fixture_max= 2.580
|time   V(typ)   V(min)   V(max)
0s        2.5V       2.43V      2.58V
383ps     2.5V       2.43V      2.577V
486ps     2.488V     2.43V      2.284V
558ps     2.34V      2.431V     2.08V
652ps     2.124V     2.343V     1.938V
738ps     2.013V     2.207V     1.867V
849ps     1.938V     2.072V     1.816V
1.111ns   1.873V     1.965V     1.77V
1.848ns   1.85V      1.93V      1.754V
10ns      1.842V     1.925V     1.743V
[Falling Waveform]
R_fixture= 50.000
V_fixture= 0.0
V_fixture_min= 0.0
V_fixture_max= 0.0
|time   V(typ)   V(min)   V(max)
0s        709.7mV    530.7mV    924mV
375ps     709.3mV    530.4mV    923.3mV
428ps     709.7mV    530.4mV    756.9mV
470ps     706.5mV    530.3mV    477.7mV
499ps     654.4mV    530.1mV    298.6mV
543ps     530.4mV    531.9mV    162.1mV
638ps     161.7mV    452.7mV    53.75mV
806ps     28.63mV    97.83mV    9.284mV
1.297ns   363.5uV    1.554mV    126.5uV
10ns      23.37uV    25.31uV    25.04uV
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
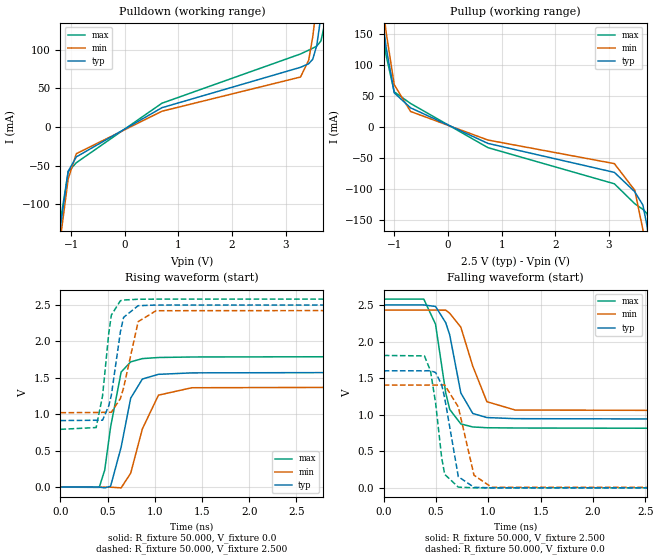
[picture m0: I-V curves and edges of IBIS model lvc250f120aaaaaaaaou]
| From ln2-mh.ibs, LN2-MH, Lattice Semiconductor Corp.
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|   Model lvc250f120aaaaaaaaou
[Model] lvc250f120aaaaaaaaou
Model_type Output
Polarity   Non-Inverting
Enable   Active-High
Vmeas =  1.250V
Cref =  0.0F
Rref =  1.000M
Vref =  0.0V
C_comp   5.000pF   4.000pF   5.500pF
[Temperature Range]   25.000   0.125k   -40.000
[Voltage Range]   2.500V   2.430V   2.580V
[C Comp Corner]
C_comp   5.000pF   4.000pF   5.500pF
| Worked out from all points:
|   slope of the pulldown table from 0 to 0.375 V, typ, clamps not added: 25.6 ohm
|   slope of the pullup table from 0 to 0.375 V, typ, clamps not added: 25.4 ohm
|   rising waveform, R_fixture 50.000, V_fixture 0.0: 20-80 % time 148ps typ, 185ps min, 122ps max; typ from 0 V to 1.59 V
|   rising waveform, R_fixture 50.000, V_fixture 2.500: 20-80 % time 107ps typ, 134ps min, 87.5ps max; typ from 0.913 V to 2.5 V
|   falling waveform, R_fixture 50.000, V_fixture 2.500: 20-80 % time 139ps typ, 172ps min, 116ps max; typ from 2.5 V to 0.921 V
|   falling waveform, R_fixture 50.000, V_fixture 0.0: 20-80 % time 106ps typ, 129ps min, 92.1ps max; typ from 1.6 V to 0 V
[Pulldown]
|Voltage   I(typ)   I(min)   I(max)
-2.5V     -1.195A    -1.198A    -1.192A
-1.208V   -132.6mA   -148.5mA   -125mA
-1.056V   -57.41mA   -67.27mA   -57.99mA
-904mV    -38.76mA   -34.6mA    -46.28mA
692mV     24.88mA    20.3mA     30.68mA
3.276V    77.14mA    64.57mA    94.41mA
3.428V    81.77mA    86.31mA    99.33mA
3.504V    87.6mA     116.8mA    101.8mA
3.58V     105.9mA    160.1mA    104.7mA
3.656V    143.2mA    211.8mA    111.2mA
3.732V    193.4mA    268.4mA    135.2mA
5V        1.311A     1.386A     1.232A
[Pullup]
|Voltage   I(typ)   I(min)   I(max)
-2.5V     1.308A     1.319A     1.301A
-1.232V   183mA      207.8mA    169.3mA
-1.156V   128.7mA    153.4mA    115.6mA
-1.004V   54.99mA    68.08mA    56.65mA
-700mV    30.85mA    24.98mA    37.86mA
744mV     -26.6mA    -21.17mA   -33.46mA
3.1V      -73.32mA   -59.2mA    -91.76mA
3.48V     -104.6mA   -102.1mA   -123.9mA
3.632V    -126.1mA   -165.8mA   -133mA
3.708V    -159.2mA   -212.9mA   -139.8mA
3.784V    -205.3mA   -265.3mA   -160.5mA
5V        -1.205A    -1.266A    -1.137A
[Ramp]
| variable   typ   min   max
dV/dt_r   0.955/0.148n   0.835/0.185n   1.084/0.122n
dV/dt_f   0.947/0.139n   0.837/0.172n   1.070/0.116n
R_load = 50.000
[Rising Waveform]
R_fixture= 50.000
V_fixture= 0.0
V_fixture_min= 0.0
V_fixture_max= 0.0
|time   V(typ)   V(min)   V(max)
0s        417.9nV    3.317uV    97.16nV
411ps     170.4uV    -338.2uV   -3.272mV
469ps     -9.832mV   -232.9uV   234.8mV
531ps     11.75mV    -837.3uV   823.3mV
643ps     550.3mV    -9.799mV   1.58V
744ps     1.221V     191.1mV    1.719V
868ps     1.484V     800.4mV    1.764V
1.038ns   1.548V     1.262V     1.779V
1.392ns   1.568V     1.364V     1.786V
10ns      1.591V     1.391V     1.806V
[Rising Waveform]
R_fixture= 50.000
V_fixture= 2.500
V_fixture_min= 2.430
V_fixture_max= 2.580
|time   V(typ)   V(min)   V(max)
0s        913.4mV    1.022V     793.3mV
378ps     917.9mV    1.024V     817.8mV
446ps     918.4mV    1.026V     1.252V
512ps     1.116V     1.028V     2.113V
539ps     1.26V      1.027V     2.36V
635ps     2.132V     1.216V     2.558V
669ps     2.33V      1.363V     2.568V
823ps     2.49V      2.271V     2.578V
1.013ns   2.499V     2.421V     2.58V
10ns      2.5V       2.43V      2.58V
[Falling Waveform]
R_fixture= 50.000
V_fixture= 2.500
V_fixture_min= 2.430
V_fixture_max= 2.580
|time   V(typ)   V(min)   V(max)
0s        2.5V       2.43V      2.58V
383ps     2.5V       2.43V      2.58V
495ps     2.48V      2.43V      2.238V
593ps     2.257V     2.429V     1.295V
631ps     2.09V      2.386V     1.072V
737ps     1.297V     2.196V     873.8mV
851ps     1.017V     1.664V     832.6mV
986ps     961.1mV    1.178V     821.8mV
1.256ns   945.8mV    1.064V     818.3mV
10ns      921mV      1.035V     796.5mV
[Falling Waveform]
R_fixture= 50.000
V_fixture= 0.0
V_fixture_min= 0.0
V_fixture_max= 0.0
|time   V(typ)   V(min)   V(max)
0s        1.6V       1.405V     1.81V
389ps     1.6V       1.405V     1.804V
447ps     1.602V     1.405V     1.6V
496ps     1.576V     1.405V     1.157V
554ps     1.41V      1.407V     409.4mV
583ps     1.227V     1.406V     184.1mV
713ps     152.9mV    1.106V     9.789mV
863ps     7.719mV    172.4mV    761.3uV
1.031ns   615.8uV    8.738mV    157.5uV
10ns      17.47uV    23.74uV    14.59uV
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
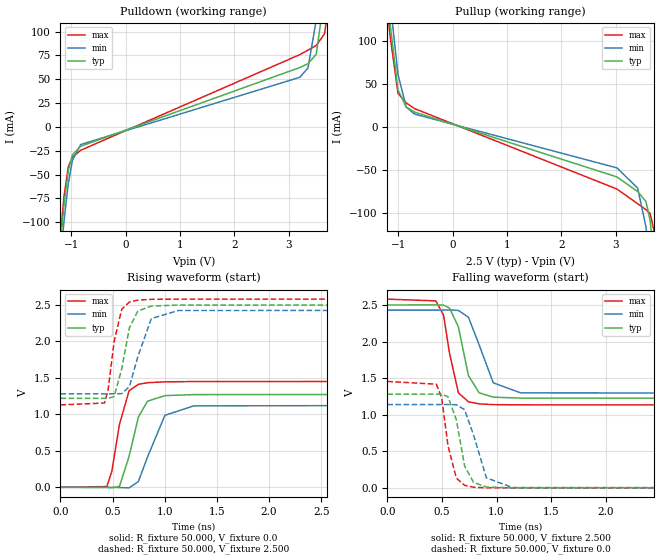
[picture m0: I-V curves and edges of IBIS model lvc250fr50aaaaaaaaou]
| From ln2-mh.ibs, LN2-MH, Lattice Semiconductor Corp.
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|   Model lvc250fr50aaaaaaaaou
[Model] lvc250fr50aaaaaaaaou
Model_type Output
Polarity   Non-Inverting
Enable   Active-High
Vmeas =  1.250V
Cref =  0.0F
Rref =  1.000M
Vref =  0.0V
C_comp   5.000pF   4.000pF   5.500pF
[Temperature Range]   25.000   0.125k   -40.000
[Voltage Range]   2.500V   2.430V   2.580V
[C Comp Corner]
C_comp   5.000pF   4.000pF   5.500pF
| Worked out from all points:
|   slope of the pulldown table from 0 to 0.375 V, typ, clamps not added: 49.2 ohm
|   slope of the pullup table from 0 to 0.375 V, typ, clamps not added: 49.2 ohm
|   rising waveform, R_fixture 50.000, V_fixture 0.0: 20-80 % time 131ps typ, 170ps min, 107ps max; typ from 0 V to 1.28 V
|   rising waveform, R_fixture 50.000, V_fixture 2.500: 20-80 % time 105ps typ, 133ps min, 84.1ps max; typ from 1.22 V to 2.5 V
|   falling waveform, R_fixture 50.000, V_fixture 2.500: 20-80 % time 113ps typ, 143ps min, 93.9ps max; typ from 2.5 V to 1.22 V
|   falling waveform, R_fixture 50.000, V_fixture 0.0: 20-80 % time 96.7ps typ, 116ps min, 84.5ps max; typ from 1.28 V to 0 V
[Pulldown]
|Voltage   I(typ)   I(min)   I(max)
-2.5V     -1.194A    -1.197A    -1.192A
-1.208V   -127.2mA   -144.2mA   -118.4mA
-1.132V   -80.31mA   -97.54mA   -71.8mA
-1.056V   -45.93mA   -59.75mA   -41.98mA
-980mV    -29.27mA   -35.14mA   -31.77mA
-828mV    -20.34mA   -18.49mA   -24.51mA
3.2V      62.31mA    52.06mA    75.82mA
3.352V    66.35mA    61.8mA     80.59mA
3.504V    76.26mA    111.7mA    85.54mA
3.656V    137.9mA    208.9mA    97.53mA
3.732V    189.7mA    266.1mA    126.9mA
5V        1.31A      1.385A     1.23A
[Pullup]
|Voltage   I(typ)   I(min)   I(max)
-2.5V     1.307A     1.319A     1.3A
-1.232V   179.3mA    205mA      164.7mA
-1.156V   123.5mA    149.8mA    108.7mA
-1.004V   42.92mA    61.02mA    39.08mA
-852mV    23.03mA    23.07mA    27.85mA
-700mV    17.25mA    14.93mA    21.27mA
3.024V    -58.05mA   -47.55mA   -72.11mA
3.404V    -74.96mA   -70.94mA   -89.09mA
3.556V    -86.45mA   -115.7mA   -95.91mA
3.632V    -108.1mA   -157mA     -100.1mA
3.784V    -196.1mA   -259.3mA   -142mA
5V        -1.201A    -1.263A    -1.132A
[Ramp]
| variable   typ   min   max
dV/dt_r   0.767/0.131n   0.681/0.170n   0.872/0.107n
dV/dt_f   0.767/0.113n   0.687/0.144n   0.870/93.926p
R_load = 50.000
[Rising Waveform]
R_fixture= 50.000
V_fixture= 0.0
V_fixture_min= 0.0
V_fixture_max= 0.0
|time   V(typ)   V(min)   V(max)
0s        646.5nV    4.786uV    156.5nV
445ps     -2.024mV   -294.7uV   10.42mV
493ps     -6.387mV   -108.3uV   223.2mV
566ps     13.35mV    -3.033mV   865.3mV
658ps     424.2mV    -7.251mV   1.324V
747ps     964.1mV    78.86mV    1.412V
834ps     1.18V      414mV      1.434V
1.001ns   1.257V     986.7mV    1.446V
1.277ns   1.271V     1.117V     1.45V
10ns      1.278V     1.135V     1.454V
[Rising Waveform]
R_fixture= 50.000
V_fixture= 2.500
V_fixture_min= 2.430
V_fixture_max= 2.580
|time   V(typ)   V(min)   V(max)
0s        1.22V      1.282V     1.13V
422ps     1.22V      1.282V     1.156V
456ps     1.219V     1.282V     1.327V
515ps     1.245V     1.283V     2.001V
587ps     1.623V     1.284V     2.44V
661ps     2.188V     1.381V     2.54V
742ps     2.417V     1.792V     2.567V
871ps     2.485V     2.313V     2.577V
1.13ns    2.499V     2.424V     2.58V
10ns      2.5V       2.43V      2.58V
[Falling Waveform]
R_fixture= 50.000
V_fixture= 2.500
V_fixture_min= 2.430
V_fixture_max= 2.580
|time   V(typ)   V(min)   V(max)
0s        2.5V       2.43V      2.58V
444ps     2.501V     2.43V      2.556V
515ps     2.498V     2.43V      2.36V
569ps     2.458V     2.432V     1.846V
651ps     2.201V     2.425V     1.298V
743ps     1.534V     2.332V     1.177V
841ps     1.299V     1.954V     1.148V
970ps     1.24V      1.436V     1.138V
1.22ns    1.227V     1.299V     1.135V
10ns      1.221V     1.285V     1.13V
[Falling Waveform]
R_fixture= 50.000
V_fixture= 0.0
V_fixture_min= 0.0
V_fixture_max= 0.0
|time   V(typ)   V(min)   V(max)
0s        1.28V      1.139V     1.455V
449ps     1.281V     1.139V     1.417V
497ps     1.28V      1.139V     1.238V
556ps     1.245V     1.14V      573.6mV
632ps     931.2mV    1.136V     133.5mV
708ps     297.6mV    1.069V     33.97mV
790ps     74.43mV    721.4mV    8.349mV
907ps     11.76mV    136.9mV    1.397mV
1.147ns   502uV      4.714mV    161.3uV
10ns      24.3uV     30.68uV    21.66uV
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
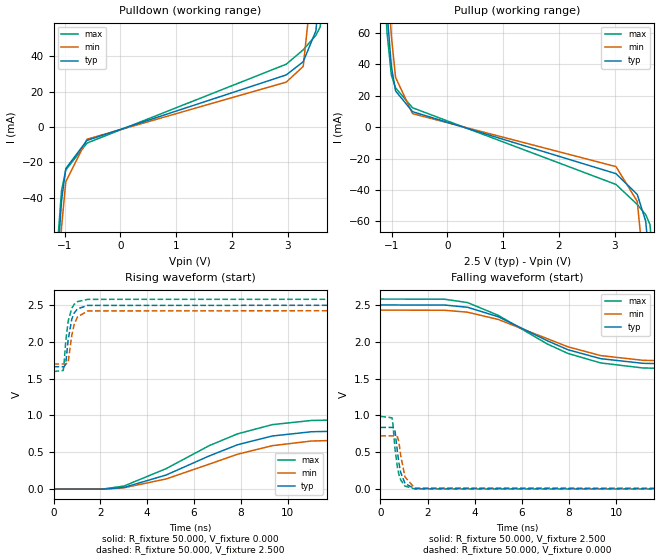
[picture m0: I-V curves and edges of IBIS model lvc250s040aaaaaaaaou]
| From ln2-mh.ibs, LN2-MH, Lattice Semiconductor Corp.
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|   Model lvc250s040aaaaaaaaou
[Model] lvc250s040aaaaaaaaou
Model_type Output
Polarity   Non-Inverting
Enable   Active-High
Vmeas =  1.250V
Cref =  0.0F
Rref =  1.000M
Vref =  0.0V
C_comp   5.000pF   4.000pF   5.500pF
[Temperature Range]   25.000   0.125k   -40.000
[Voltage Range]   2.500V   2.430V   2.580V
[C Comp Corner]
C_comp   5.000pF   4.000pF   5.500pF
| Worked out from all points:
|   slope of the pulldown table from 0 to 0.375 V, typ, clamps not added: 97.7 ohm
|   slope of the pullup table from 0 to 0.375 V, typ, clamps not added: 97.8 ohm
|   rising waveform, R_fixture 50.000, V_fixture 0.000: 20-80 % time 3.97ns typ, 4.28ns min, 3.95ns max; typ from 0 V to 0.838 V
|   rising waveform, R_fixture 50.000, V_fixture 2.500: 20-80 % time 240ps typ, 252ps min, 227ps max; typ from 1.66 V to 2.5 V
|   falling waveform, R_fixture 50.000, V_fixture 2.500: 20-80 % time 3.5ns typ, 3.69ns min, 3.54ns max; typ from 2.5 V to 1.66 V
|   falling waveform, R_fixture 50.000, V_fixture 0.000: 20-80 % time 243ps typ, 256ps min, 232ps max; typ from 0.838 V to 0 V
[Pulldown]
|Voltage   I(typ)   I(min)   I(max)
-2.5V     -1.193A    -1.196A    -1.191A
-1.208V   -124.9mA   -142.3mA   -115.7mA
-1.132V   -77.28mA   -95.08mA   -67.94mA
-1.056V   -41.5mA    -56.51mA   -35.82mA
-980mV    -23.44mA   -30.89mA   -24.21mA
-600mV    -7.479mA   -6.85mA    -9.008mA
2.972V    29.56mA    25.5mA     35.62mA
3.276V    37.04mA    34.38mA    43.78mA
3.504V    54.56mA    102mA      52.02mA
3.58V     83.28mA    149.3mA    56.75mA
3.732V    182.9mA    261.6mA    112.9mA
5V        1.308A     1.384A     1.228A
[Pullup]
|Voltage   I(typ)   I(min)   I(max)
-2.5V     1.307A     1.318A     1.3A
-1.156V   121.7mA    148.3mA    106.4mA
-1.08V    73.14mA    98.56mA    59.79mA
-1.004V   38.84mA    58.25mA    33.22mA
-928mV    23.06mA    31.67mA    24.99mA
-624mV    9.842mA    8.614mA    12.33mA
3.024V    -29.66mA   -25.16mA   -36.52mA
3.404V    -42.85mA   -47.28mA   -49.27mA
3.556V    -59.94mA   -101.7mA   -55.76mA
3.632V    -89.74mA   -146.2mA   -62.01mA
3.784V    -186.1mA   -251.8mA   -124.5mA
5V        -1.197A    -1.259A    -1.126A
[Ramp]
| variable   typ   min   max
dV/dt_r   0.513/3.979n   0.443/4.289n   0.605/3.960n
dV/dt_f   0.514/3.502n   0.448/3.709n   0.603/3.545n
R_load = 50.000
[Rising Waveform]
R_fixture = 50.000
V_fixture = 0.000
V_fixture_min = 0.000
V_fixture_max = 0.000
|  time   V(typ)   V(min)   V(max)
0s        2.092uV    10.17uV    1.204uV
2.107ns   441.3uV    861.6uV    1.588mV
3.011ns   23.62mV    19.13mV    42.74mV
4.808ns   191.7mV    138.3mV    278.1mV
6.654ns   451.3mV    339.6mV    590.8mV
7.861ns   602.7mV    473.8mV    750.4mV
9.347ns   721.5mV    590.1mV    875.7mV
11.01ns   779.1mV    653.2mV    932.2mV
18.84ns   834.1mV    719.2mV    983.7mV
50ns      837.9mV    723.6mV    988.2mV
[Rising Waveform]
R_fixture = 50.000
V_fixture = 2.500
V_fixture_min = 2.430
V_fixture_max = 2.580
|  time   V(typ)   V(min)   V(max)
0s        1.662V     1.699V     1.596V
414ps     1.662V     1.699V     1.611V
447ps     1.661V     1.699V     1.689V
519ps     1.694V     1.699V     1.994V
623ps     2.021V     1.718V     2.275V
780ps     2.309V     2.088V     2.456V
883ps     2.39V      2.237V     2.508V
1.02ns    2.446V     2.336V     2.545V
1.46ns    2.494V     2.419V     2.576V
50ns      2.5V       2.43V      2.58V
[Falling Waveform]
R_fixture = 50.000
V_fixture = 2.500
V_fixture_min = 2.430
V_fixture_max = 2.580
|  time   V(typ)   V(min)   V(max)
0s        2.5V       2.43V      2.58V
2.714ns   2.499V     2.428V     2.578V
3.689ns   2.469V     2.402V     2.533V
5ns       2.34V      2.303V     2.359V
7.08ns    2.014V     2.042V     1.97V
7.954ns   1.892V     1.932V     1.842V
9.341ns   1.771V     1.813V     1.713V
11.13ns   1.708V     1.749V     1.645V
17.31ns   1.666V     1.703V     1.601V
50ns      1.662V     1.699V     1.596V
[Falling Waveform]
R_fixture = 50.000
V_fixture = 0.000
V_fixture_min = 0.000
V_fixture_max = 0.000
|  time   V(typ)   V(min)   V(max)
0s        837.9mV    723.6mV    988.2mV
491ps     837.8mV    723.3mV    968.5mV
531ps     838.2mV    723.5mV    883.4mV
614ps     805.5mV    723.6mV    562.2mV
723ps     501.6mV    710.6mV    292.8mV
783ps     357.6mV    643.3mV    202.3mV
861ps     225.9mV    456.2mV    125.5mV
1.044ns   76.74mV    165.7mV    41.58mV
1.449ns   7.515mV    16.9mV     4.013mV
50ns      2.092uV    10.17uV    1.204uV
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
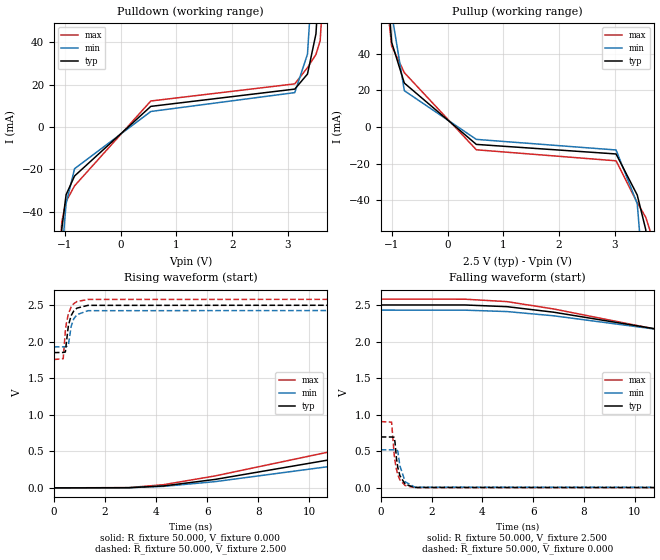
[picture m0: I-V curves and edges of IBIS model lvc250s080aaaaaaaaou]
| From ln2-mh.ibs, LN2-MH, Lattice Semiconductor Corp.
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|   Model lvc250s080aaaaaaaaou
[Model] lvc250s080aaaaaaaaou
Model_type Output
Polarity   Non-Inverting
Enable   Active-High
Vmeas =  1.250V
Cref =  0.0F
Rref =  1.000M
Vref =  0.0V
C_comp   5.000pF   4.000pF   5.500pF
[Temperature Range]   25.000   0.125k   -40.000
[Voltage Range]   2.500V   2.430V   2.580V
[C Comp Corner]
C_comp   5.000pF   4.000pF   5.500pF
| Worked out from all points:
|   slope of the pulldown table from 0 to 0.375 V, typ, clamps not added: 51.3 ohm
|   slope of the pullup table from 0 to 0.375 V, typ, clamps not added: 50.7 ohm
|   rising waveform, R_fixture 50.000, V_fixture 0.000: 20-80 % time 7.7ns typ, 7.45ns min, 8.16ns max; typ from 0 V to 0.696 V
|   rising waveform, R_fixture 50.000, V_fixture 2.500: 20-80 % time 207ps typ, 213ps min, 201ps max; typ from 1.85 V to 2.5 V
|   falling waveform, R_fixture 50.000, V_fixture 2.500: 20-80 % time 7.54ns typ, 7.26ns min, 7.94ns max; typ from 2.5 V to 1.85 V
|   falling waveform, R_fixture 50.000, V_fixture 0.000: 20-80 % time 206ps typ, 213ps min, 201ps max; typ from 0.696 V to 0 V
[Pulldown]
|Voltage   I(typ)   I(min)   I(max)
-2.5V     -1.193A    -1.196A    -1.19A
-1.132V   -81.49mA   -97.97mA   -73.3mA
-1.056V   -47.95mA   -60.51mA   -44.7mA
-980mV    -32.05mA   -36.26mA   -35.19mA
-828mV    -23.16mA   -19.74mA   -27.81mA
540mV     9.707mA    7.295mA    12.25mA
3.124V    17.87mA    16.21mA    20.34mA
3.352V    24.97mA    34.39mA    28.01mA
3.504V    43.96mA    97.16mA    34.24mA
3.58V     76.44mA    145.7mA    40.74mA
3.732V    179.6mA    259.3mA    106.8mA
5V        1.307A     1.383A     1.226A
[Pullup]
|Voltage   I(typ)   I(min)   I(max)
-2.5V     1.307A     1.318A     1.3A
-1.156V   124.7mA    150.2mA    110.5mA
-1.08V    77.87mA    101.3mA    66.77mA
-1.004V   46.29mA    62.28mA    44.31mA
-776mV    23.97mA    19.8mA     29.66mA
516mV     -9.544mA   -6.801mA   -12.49mA
3.024V    -14.77mA   -12.6mA    -18.52mA
3.404V    -37.23mA   -41.96mA   -41.42mA
3.556V    -56.06mA   -98.76mA   -49.36mA
3.632V    -87.15mA   -143.9mA   -56.52mA
3.784V    -184.6mA   -250.2mA   -122.2mA
5V        -1.196A    -1.258A    -1.125A
[Ramp]
| variable   typ   min   max
dV/dt_r   0.428/7.704n   0.319/7.471n   0.557/8.167n
dV/dt_f   0.402/7.564n   0.309/7.279n   0.508/7.962n
R_load = 50.000
[Rising Waveform]
R_fixture = 50.000
V_fixture = 0.000
V_fixture_min = 0.000
V_fixture_max = 0.000
|  time   V(typ)   V(min)   V(max)
0s        45.37uV    53.45uV    41.42uV
2.931ns   1.74mV     2.341mV    3.57mV
4.291ns   26.35mV    20.6mV     43.26mV
6.314ns   115.8mV    85.22mV    163.7mV
10.88ns   389.2mV    296.9mV    499.6mV
13.53ns   521.5mV    396.2mV    665.4mV
16.3ns    615.1mV    464.7mV    787.6mV
19.53ns   674.8mV    505.6mV    871.4mV
23ns      687mV      513.3mV    897mV
50ns      695.8mV    520.3mV    905.9mV
[Rising Waveform]
R_fixture = 50.000
V_fixture = 2.500
V_fixture_min = 2.430
V_fixture_max = 2.580
|  time   V(typ)   V(min)   V(max)
0s        1.849V     1.927V     1.754V
367ps     1.851V     1.928V     1.766V
451ps     1.857V     1.929V     2.143V
488ps     1.976V     1.93V      2.244V
570ps     2.22V      1.951V     2.381V
676ps     2.354V     2.205V     2.471V
776ps     2.416V     2.308V     2.517V
904ps     2.457V     2.368V     2.547V
1.335ns   2.495V     2.422V     2.576V
50ns      2.5V       2.43V      2.58V
[Falling Waveform]
R_fixture = 50.000
V_fixture = 2.500
V_fixture_min = 2.430
V_fixture_max = 2.580
|  time   V(typ)   V(min)   V(max)
0s        2.5V       2.43V      2.58V
3.319ns   2.5V       2.429V     2.579V
4.969ns   2.477V     2.41V      2.546V
6.811ns   2.401V     2.352V     2.445V
11.39ns   2.141V     2.143V     2.13V
14.13ns   2.01V      2.042V     1.97V
16.77ns   1.923V     1.978V     1.86V
19.93ns   1.869V     1.943V     1.784V
23.81ns   1.856V     1.935V     1.76V
50ns      1.849V     1.927V     1.754V
[Falling Waveform]
R_fixture = 50.000
V_fixture = 0.000
V_fixture_min = 0.000
V_fixture_max = 0.000
|  time   V(typ)   V(min)   V(max)
0s        695.8mV    520.3mV    905.9mV
428ps     695.2mV    520mV      898.5mV
528ps     692mV      519.7mV    465.8mV
563ps     626mV      519.9mV    366mV
621ps     399.7mV    520.3mV    251.7mV
673ps     279.3mV    502.2mV    181.9mV
754ps     168.5mV    302.4mV    110.8mV
963ps     48.93mV    83.25mV    31.51mV
1.343ns   5.526mV    9.819mV    3.443mV
50ns      45.37uV    53.45uV    41.42uV
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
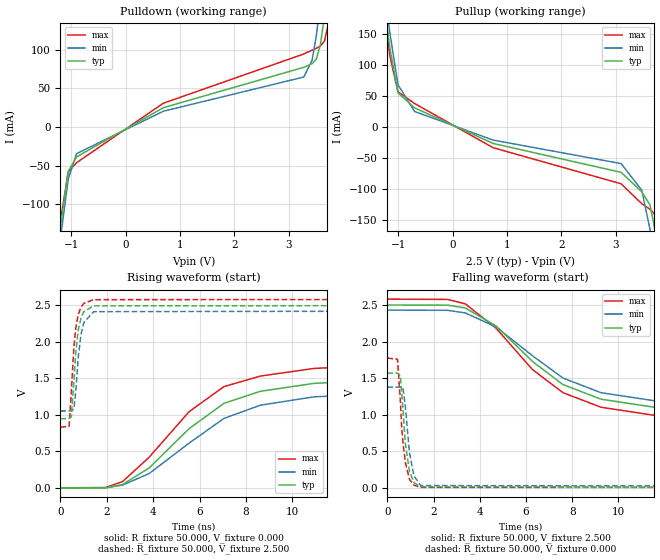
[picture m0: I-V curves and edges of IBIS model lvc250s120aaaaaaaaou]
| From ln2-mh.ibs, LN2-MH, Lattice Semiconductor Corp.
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|   Model lvc250s120aaaaaaaaou
[Model] lvc250s120aaaaaaaaou
Model_type Output
Polarity   Non-Inverting
Enable   Active-High
Vmeas =  1.250V
Cref =  0.0F
Rref =  1.000M
Vref =  0.0V
C_comp   5.000pF   4.000pF   5.500pF
[Temperature Range]   25.000   0.125k   -40.000
[Voltage Range]   2.500V   2.430V   2.580V
[C Comp Corner]
C_comp   5.000pF   4.000pF   5.500pF
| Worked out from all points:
|   slope of the pulldown table from 0 to 0.375 V, typ, clamps not added: 25.6 ohm
|   slope of the pullup table from 0 to 0.375 V, typ, clamps not added: 25.4 ohm
|   rising waveform, R_fixture 50.000, V_fixture 0.000: 20-80 % time 3.85ns typ, 4.07ns min, 3.67ns max; typ from 0 V to 1.57 V
|   rising waveform, R_fixture 50.000, V_fixture 2.500: 20-80 % time 242ps typ, 255ps min, 231ps max; typ from 0.945 V to 2.5 V
|   falling waveform, R_fixture 50.000, V_fixture 2.500: 20-80 % time 3.94ns typ, 4.03ns min, 3.84ns max; typ from 2.5 V to 0.945 V
|   falling waveform, R_fixture 50.000, V_fixture 0.000: 20-80 % time 265ps typ, 281ps min, 253ps max; typ from 1.57 V to 0 V
[Pulldown]
|Voltage   I(typ)   I(min)   I(max)
-2.5V     -1.195A    -1.198A    -1.192A
-1.208V   -132.6mA   -148.5mA   -125mA
-1.056V   -57.41mA   -67.27mA   -57.99mA
-904mV    -38.76mA   -34.6mA    -46.28mA
692mV     24.88mA    20.3mA     30.68mA
3.276V    77.14mA    64.57mA    94.41mA
3.428V    81.77mA    86.31mA    99.33mA
3.504V    87.6mA     116.8mA    101.8mA
3.58V     105.9mA    160.1mA    104.7mA
3.656V    143.2mA    211.8mA    111.2mA
3.732V    193.4mA    268.4mA    135.2mA
5V        1.311A     1.386A     1.232A
[Pullup]
|Voltage   I(typ)   I(min)   I(max)
-2.5V     1.308A     1.319A     1.301A
-1.232V   183mA      207.8mA    169.3mA
-1.156V   128.7mA    153.4mA    115.6mA
-1.004V   54.99mA    68.08mA    56.65mA
-700mV    30.85mA    24.98mA    37.86mA
744mV     -26.6mA    -21.17mA   -33.46mA
3.1V      -73.32mA   -59.2mA    -91.76mA
3.48V     -104.6mA   -102.1mA   -123.9mA
3.632V    -126.1mA   -165.8mA   -133mA
3.708V    -159.2mA   -212.9mA   -139.8mA
3.784V    -205.3mA   -265.3mA   -160.5mA
5V        -1.205A    -1.266A    -1.137A
[Ramp]
| variable   typ   min   max
dV/dt_r   0.964/3.845n   0.846/4.077n   1.089/3.679n
dV/dt_f   0.956/3.934n   0.849/4.026n   1.074/3.843n
R_load = 50.000
[Rising Waveform]
R_fixture = 50.000
V_fixture = 0.000
V_fixture_min = 0.000
V_fixture_max = 0.000
|  time   V(typ)   V(min)   V(max)
0s        29.79uV    34.05uV    26.85uV
1.955ns   1.356mV    1.951mV    4.875mV
2.677ns   45.71mV    36.96mV    85.88mV
3.825ns   272.5mV    195.8mV    418.6mV
5.545ns   808.9mV    610.9mV    1.041V
7.049ns   1.155V     949.1mV    1.384V
8.618ns   1.32V      1.13V      1.528V
10.92ns   1.428V     1.244V     1.632V
18.94ns   1.552V     1.359V     1.763V
50ns      1.568V     1.378V     1.774V
[Rising Waveform]
R_fixture = 50.000
V_fixture = 2.500
V_fixture_min = 2.430
V_fixture_max = 2.580
|  time   V(typ)   V(min)   V(max)
0s        944.6mV    1.05V      828.6mV
375ps     948.3mV    1.052V     842.7mV
470ps     973.4mV    1.054V     1.317V
579ps     1.458V     1.076V     1.922V
660ps     1.849V     1.311V     2.182V
769ps     2.158V     1.788V     2.372V
887ps     2.324V     2.101V     2.471V
1.012ns   2.409V     2.263V     2.523V
1.436ns   2.488V     2.409V     2.573V
50ns      2.5V       2.43V      2.58V
[Falling Waveform]
R_fixture = 50.000
V_fixture = 2.500
V_fixture_min = 2.430
V_fixture_max = 2.580
|  time   V(typ)   V(min)   V(max)
0s        2.5V       2.43V      2.58V
2.596ns   2.498V     2.427V     2.576V
3.366ns   2.46V      2.392V     2.517V
4.709ns   2.213V     2.199V     2.181V
6.281ns   1.728V     1.806V     1.617V
7.601ns   1.412V     1.501V     1.301V
9.247ns   1.212V     1.301V     1.102V
11.84ns   1.088V     1.177V     978mV
20.14ns   958.1mV    1.067V     837.8mV
50ns      944.6mV    1.05V      828.6mV
[Falling Waveform]
R_fixture = 50.000
V_fixture = 0.000
V_fixture_min = 0.000
V_fixture_max = 0.000
|  time   V(typ)   V(min)   V(max)
0s        1.568V     1.378V     1.774V
442ps     1.569V     1.378V     1.758V
560ps     1.534V     1.378V     1.211V
618ps     1.324V     1.377V     851mV
679ps     1.056V     1.364V     612mV
783ps     597.5mV    1.099V     344mV
957ps     226.5mV    484.7mV    117.4mV
1.151ns   71.62mV    165.7mV    36.57mV
1.441ns   13.73mV    31.97mV    7.165mV
50ns      29.79uV    34.05uV    26.85uV
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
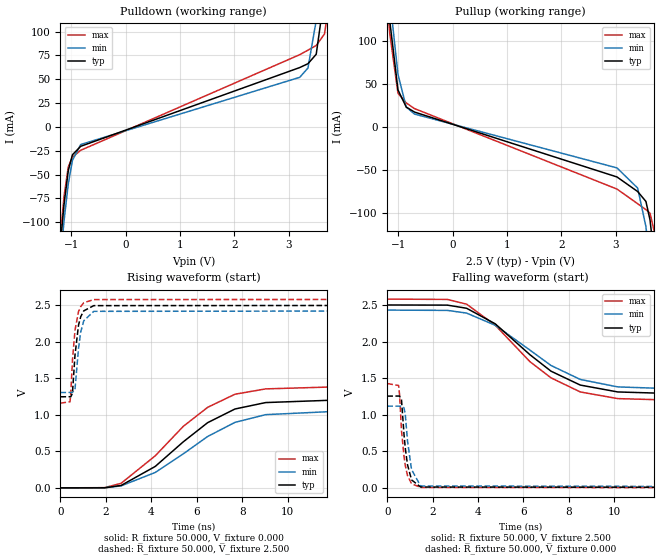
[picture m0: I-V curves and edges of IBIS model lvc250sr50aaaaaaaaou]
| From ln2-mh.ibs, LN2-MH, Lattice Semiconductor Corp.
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|   Model lvc250sr50aaaaaaaaou
[Model] lvc250sr50aaaaaaaaou
Model_type Output
Polarity   Non-Inverting
Enable   Active-High
Vmeas =  1.250V
Cref =  0.0F
Rref =  1.000M
Vref =  0.0V
C_comp   5.000pF   4.000pF   5.500pF
[Temperature Range]   25.000   0.125k   -40.000
[Voltage Range]   2.500V   2.430V   2.580V
[C Comp Corner]
C_comp   5.000pF   4.000pF   5.500pF
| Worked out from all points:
|   slope of the pulldown table from 0 to 0.375 V, typ, clamps not added: 49.2 ohm
|   slope of the pullup table from 0 to 0.375 V, typ, clamps not added: 49.2 ohm
|   rising waveform, R_fixture 50.000, V_fixture 0.000: 20-80 % time 3.11ns typ, 3.42ns min, 3.01ns max; typ from 0 V to 1.25 V
|   rising waveform, R_fixture 50.000, V_fixture 2.500: 20-80 % time 237ps typ, 249ps min, 228ps max; typ from 1.25 V to 2.5 V
|   falling waveform, R_fixture 50.000, V_fixture 2.500: 20-80 % time 3.06ns typ, 3.24ns min, 3.04ns max; typ from 2.5 V to 1.25 V
|   falling waveform, R_fixture 50.000, V_fixture 0.000: 20-80 % time 250ps typ, 264ps min, 242ps max; typ from 1.25 V to 0 V
[Pulldown]
|Voltage   I(typ)   I(min)   I(max)
-2.5V     -1.194A    -1.197A    -1.192A
-1.208V   -127.2mA   -144.2mA   -118.4mA
-1.132V   -80.31mA   -97.54mA   -71.8mA
-1.056V   -45.93mA   -59.75mA   -41.98mA
-980mV    -29.27mA   -35.14mA   -31.77mA
-828mV    -20.34mA   -18.49mA   -24.51mA
3.2V      62.31mA    52.06mA    75.82mA
3.352V    66.35mA    61.8mA     80.59mA
3.504V    76.26mA    111.7mA    85.54mA
3.656V    137.9mA    208.9mA    97.53mA
3.732V    189.7mA    266.1mA    126.9mA
5V        1.31A      1.385A     1.23A
[Pullup]
|Voltage   I(typ)   I(min)   I(max)
-2.5V     1.307A     1.319A     1.3A
-1.232V   179.3mA    205mA      164.7mA
-1.156V   123.5mA    149.8mA    108.7mA
-1.004V   42.92mA    61.02mA    39.08mA
-852mV    23.03mA    23.07mA    27.85mA
-700mV    17.25mA    14.93mA    21.27mA
3.024V    -58.05mA   -47.55mA   -72.11mA
3.404V    -74.96mA   -70.94mA   -89.09mA
3.556V    -86.45mA   -115.7mA   -95.91mA
3.632V    -108.1mA   -157mA     -100.1mA
3.784V    -196.1mA   -259.3mA   -142mA
5V        -1.201A    -1.263A    -1.132A
[Ramp]
| variable   typ   min   max
dV/dt_r   0.768/3.114n   0.684/3.425n   0.873/3.015n
dV/dt_f   0.769/3.063n   0.690/3.250n   0.870/3.041n
R_load = 50.000
[Rising Waveform]
R_fixture = 50.000
V_fixture = 0.000
V_fixture_min = 0.000
V_fixture_max = 0.000
|  time   V(typ)   V(min)   V(max)
0s        1.825uV    6.585uV    2.47uV
1.939ns   783.9uV    1.169mV    2.789mV
2.667ns   32.51mV    27mV       61.95mV
4.169ns   292.8mV    210.3mV    437.8mV
5.407ns   630.3mV    466.2mV    841.8mV
6.476ns   891.4mV    702.3mV    1.101V
7.676ns   1.078V     895.1mV    1.28V
9.029ns   1.166V     1.001V     1.353V
16.32ns   1.247V     1.107V     1.419V
50ns      1.254V     1.117V     1.426V
[Rising Waveform]
R_fixture = 50.000
V_fixture = 2.500
V_fixture_min = 2.430
V_fixture_max = 2.580
|  time   V(typ)   V(min)   V(max)
0s        1.245V     1.304V     1.158V
421ps     1.246V     1.304V     1.177V
454ps     1.244V     1.305V     1.287V
529ps     1.295V     1.305V     1.749V
639ps     1.812V     1.343V     2.154V
795ps     2.225V     1.909V     2.41V
894ps     2.341V     2.134V     2.48V
1.026ns   2.42V      2.284V     2.53V
1.465ns   2.491V     2.413V     2.574V
50ns      2.5V       2.43V      2.58V
[Falling Waveform]
R_fixture = 50.000
V_fixture = 2.500
V_fixture_min = 2.430
V_fixture_max = 2.580
|  time   V(typ)   V(min)   V(max)
0s        2.5V       2.43V      2.58V
2.648ns   2.498V     2.426V     2.576V
3.495ns   2.455V     2.389V     2.511V
4.755ns   2.243V     2.223V     2.224V
6.287ns   1.82V      1.883V     1.725V
7.215ns   1.595V     1.673V     1.504V
8.506ns   1.405V     1.482V     1.311V
10.16ns   1.311V     1.38V      1.22V
16.59ns   1.252V     1.312V     1.165V
50ns      1.245V     1.304V     1.158V
[Falling Waveform]
R_fixture = 50.000
V_fixture = 0.000
V_fixture_min = 0.000
V_fixture_max = 0.000
|  time   V(typ)   V(min)   V(max)
0s        1.254V     1.117V     1.426V
498ps     1.255V     1.117V     1.399V
538ps     1.255V     1.117V     1.282V
626ps     1.201V     1.117V     777.1mV
736ps     726.3mV    1.094V     431.3mV
796ps     531.5mV    989.4mV    300.1mV
890ps     315.5mV    639.7mV    167.6mV
1.068ns   109.3mV    249.8mV    56.76mV
1.468ns   11.02mV    25.75mV    5.79mV
50ns      1.825uV    6.585uV    2.47uV
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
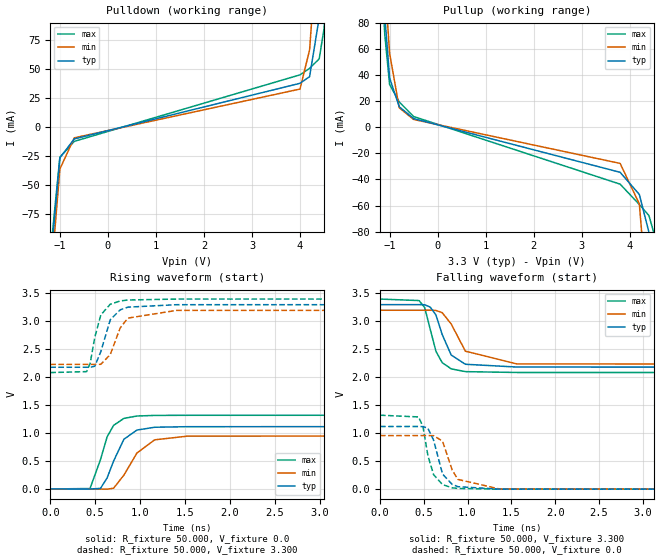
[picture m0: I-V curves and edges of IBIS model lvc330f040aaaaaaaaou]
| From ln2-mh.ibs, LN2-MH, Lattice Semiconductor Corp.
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|   Model lvc330f040aaaaaaaaou
[Model] lvc330f040aaaaaaaaou
Model_type Output
Polarity   Non-Inverting
Enable   Active-High
Vmeas =  1.650V
Cref =  0.0F
Rref =  1.000M
Vref =  0.0V
C_comp   5.000pF   4.000pF   5.500pF
[Temperature Range]   25.000   0.125k   -40.000
[Voltage Range]   3.300V   3.200V   3.400V
[C Comp Corner]
C_comp   5.000pF   4.000pF   5.500pF
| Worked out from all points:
|   slope of the pulldown table from 0 to 0.495 V, typ, clamps not added: 97.8 ohm
|   slope of the pullup table from 0 to 0.495 V, typ, clamps not added: 97.9 ohm
|   rising waveform, R_fixture 50.000, V_fixture 0.0: 20-80 % time 183ps typ, 234ps min, 155ps max; typ from 0 V to 1.12 V
|   rising waveform, R_fixture 50.000, V_fixture 3.300: 20-80 % time 132ps typ, 157ps min, 112ps max; typ from 2.18 V to 3.3 V
|   falling waveform, R_fixture 50.000, V_fixture 3.300: 20-80 % time 162ps typ, 203ps min, 140ps max; typ from 3.3 V to 2.18 V
|   falling waveform, R_fixture 50.000, V_fixture 0.0: 20-80 % time 123ps typ, 139ps min, 111ps max; typ from 1.12 V to 0 V
[Pulldown]
|Voltage   I(typ)   I(min)   I(max)
-3.3V     -1.889A    -1.889A    -1.885A
-1.3V     -190.6mA   -206.3mA   -182.7mA
-1.2V     -119.6mA   -137mA     -110.3mA
-1V       -26.58mA   -36.22mA   -26mA
-700mV    -10.17mA   -9.237mA   -12.29mA
4V        37.91mA    32.95mA    45.24mA
4.2V      43.71mA    66.9mA     50.86mA
4.4V      94.67mA    184.5mA    59.1mA
4.5V      159.6mA    260.2mA    84.98mA
4.6V      236.3mA    340.8mA    146.2mA
4.7V      318.5mA    424.5mA    223.2mA
6.6V      2.051A     2.152A     1.952A
[Pullup]
|Voltage   I(typ)   I(min)   I(max)
-3.3V     2.05A      2.058A     2.044A
-1.2V     153.6mA    179.9mA    138.5mA
-1.1V     84.88mA    110.9mA    70.67mA
-1V       37.66mA    56.5mA     32.62mA
-800mV    15.63mA    14.82mA    19.3mA
-500mV    6.55mA     5.856mA    8.142mA
3.8V      -34.58mA   -27.77mA   -43.65mA
4.2V      -51.54mA   -58.8mA    -59.21mA
4.4V      -80.52mA   -147.9mA   -67.74mA
4.5V      -132.3mA   -214.9mA   -80.66mA
4.6V      -200.2mA   -288.1mA   -126.3mA
6.6V      -1.893A    -1.98A     -1.804A
[Ramp]
| variable   typ   min   max
dV/dt_r   0.672/0.183n   0.573/0.234n   0.793/0.155n
dV/dt_f   0.672/0.162n   0.580/0.203n   0.789/0.140n
R_load = 50.000
[Rising Waveform]
R_fixture= 50.000
V_fixture= 0.0
V_fixture_min= 0.0
V_fixture_max= 0.0
|time   V(typ)   V(min)   V(max)
0s        4.013uV    16.57uV    1.512uV
442ps     -962.2uV   -282.9uV   7.829mV
559ps     10.29mV    -1.321mV   525.2mV
633ps     198.3mV    -3.635mV   934.1mV
705ps     500.1mV    13.36mV    1.139V
820ps     890.5mV    248.6mV    1.264V
965ps     1.055V     643.5mV    1.306V
1.163ns   1.105V     879.9mV    1.317V
1.524ns   1.115V     945.4mV    1.319V
10ns      1.119V     955.4mV    1.322V
[Rising Waveform]
R_fixture= 50.000
V_fixture= 3.300
V_fixture_min= 3.200
V_fixture_max= 3.400
|time   V(typ)   V(min)   V(max)
0s        2.179V     2.23V      2.084V
405ps     2.179V     2.231V     2.101V
444ps     2.179V     2.231V     2.25V
496ps     2.198V     2.231V     2.719V
563ps     2.46V      2.232V     3.117V
668ps     3.029V     2.407V     3.307V
778ps     3.207V     2.882V     3.366V
864ps     3.255V     3.059V     3.383V
1.405ns   3.299V     3.197V     3.4V
10ns      3.3V       3.2V       3.4V
[Falling Waveform]
R_fixture= 50.000
V_fixture= 3.300
V_fixture_min= 3.200
V_fixture_max= 3.400
|time   V(typ)   V(min)   V(max)
0s        3.3V       3.2V       3.4V
446ps     3.3V       3.2V       3.373V
510ps     3.298V     3.2V       3.249V
574ps     3.256V     3.201V     2.857V
639ps     3.115V     3.196V     2.465V
710ps     2.766V     3.157V     2.263V
813ps     2.399V     2.954V     2.152V
975ps     2.234V     2.468V     2.102V
1.563ns   2.184V     2.24V      2.087V
10ns      2.18V      2.233V     2.084V
[Falling Waveform]
R_fixture= 50.000
V_fixture= 0.0
V_fixture_min= 0.0
V_fixture_max= 0.0
|time   V(typ)   V(min)   V(max)
0s        1.121V     959mV      1.323V
440ps     1.121V     958.8mV    1.292V
490ps     1.12V      958.7mV    1.124V
547ps     1.089V     959.3mV    599mV
612ps     875.1mV    957.1mV    259.5mV
714ps     270.6mV    858.9mV    81.51mV
824ps     85.45mV    344.1mV    24.83mV
889ps     44.52mV    175mV      12.51mV
1.368ns   551uV      2.26mV     237.6uV
10ns      36.19uV    45.94uV    30.95uV
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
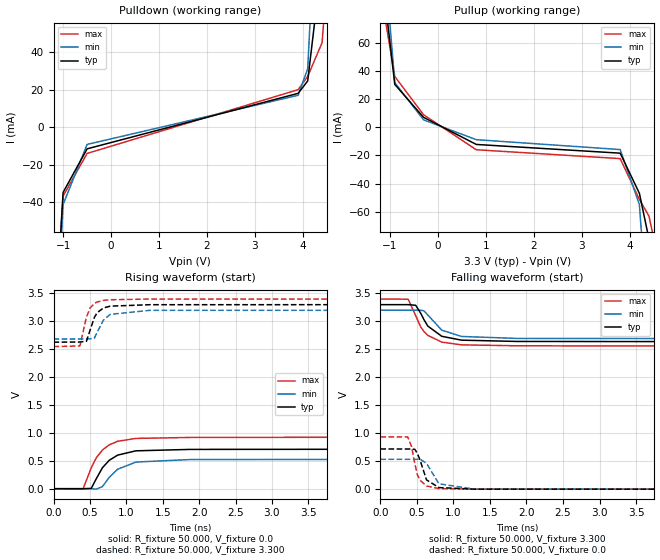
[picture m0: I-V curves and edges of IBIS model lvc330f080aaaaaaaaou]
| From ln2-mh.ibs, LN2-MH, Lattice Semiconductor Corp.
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|   Model lvc330f080aaaaaaaaou
[Model] lvc330f080aaaaaaaaou
Model_type Output
Polarity   Non-Inverting
Enable   Active-High
Vmeas =  1.650V
Cref =  0.0F
Rref =  1.000M
Vref =  0.0V
C_comp   5.000pF   4.000pF   5.500pF
[Temperature Range]   25.000   0.125k   -40.000
[Voltage Range]   3.300V   3.200V   3.400V
[C Comp Corner]
C_comp   5.000pF   4.000pF   5.500pF
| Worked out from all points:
|   slope of the pulldown table from 0 to 0.495 V, typ, clamps not added: 54.2 ohm
|   slope of the pullup table from 0 to 0.495 V, typ, clamps not added: 53.5 ohm
|   rising waveform, R_fixture 50.000, V_fixture 0.0: 20-80 % time 258ps typ, 275ps min, 251ps max; typ from 0 V to 0.713 V
|   rising waveform, R_fixture 50.000, V_fixture 3.300: 20-80 % time 121ps typ, 147ps min, 101ps max; typ from 2.63 V to 3.3 V
|   falling waveform, R_fixture 50.000, V_fixture 3.300: 20-80 % time 242ps typ, 258ps min, 232ps max; typ from 3.3 V to 2.63 V
|   falling waveform, R_fixture 50.000, V_fixture 0.0: 20-80 % time 115ps typ, 138ps min, 100ps max; typ from 0.719 V to 0 V
[Pulldown]
|Voltage   I(typ)   I(min)   I(max)
-3.3V     -1.888A    -1.889A    -1.884A
-1.3V     -192.7mA   -207.9mA   -185mA
-1.2V     -122.6mA   -139.3mA   -113.9mA
-1V       -34.79mA   -41.24mA   -36.74mA
-500mV    -11.57mA   -9.217mA   -14.02mA
3.9V      18.02mA    16.98mA    19.97mA
4.1V      24.62mA    31.12mA    27.04mA
4.4V      89.35mA    181.9mA    45.02mA
4.5V      156.5mA    258.2mA    77.93mA
4.6V      234.1mA    339.2mA    142.8mA
4.7V      316.8mA    423.2mA    221mA
6.6V      2.051A     2.152A     1.952A
[Pullup]
|Voltage   I(typ)   I(min)   I(max)
-3.3V     2.05A      2.058A     2.043A
-1.2V     156mA      181.6mA    141.7mA
-1.1V     89.07mA    113.5mA    76.66mA
-900mV    30.3mA     31.55mA    35.9mA
-300mV    6.959mA    5.173mA    8.774mA
800mV     -12.27mA   -8.891mA   -16.03mA
3.8V      -18.46mA   -15.9mA    -22.32mA
4.2V      -46.88mA   -54.84mA   -51.24mA
4.4V      -79.23mA   -146.5mA   -63.05mA
4.5V      -132mA     -213.9mA   -78.84mA
4.6V      -200.3mA   -287.5mA   -126.2mA
6.6V      -1.899A    -1.982A    -1.811A
[Ramp]
| variable   typ   min   max
dV/dt_r   0.428/0.258n   0.317/0.276n   0.558/0.251n
dV/dt_f   0.400/0.242n   0.306/0.259n   0.509/0.232n
R_load = 50.000
[Rising Waveform]
R_fixture= 50.000
V_fixture= 0.0
V_fixture_min= 0.0
V_fixture_max= 0.0
|time   V(typ)   V(min)   V(max)
0s        3.331uV    16.33uV    1.177uV
404ps     -45.95uV   -313.6uV   -7.061mV
518ps     5.181mV    -446.1uV   374.1mV
587ps     178.4mV    -8.559mV   553.3mV
672ps     376mV      37.56mV    693.8mV
766ps     510.1mV    205.4mV    786.9mV
881ps     602mV      348.9mV    850mV
1.132ns   679mV      477.6mV    901.6mV
1.877ns   704.4mV    522.8mV    918.8mV
10ns      712.8mV    528.5mV    930.5mV
[Rising Waveform]
R_fixture= 50.000
V_fixture= 3.300
V_fixture_min= 3.200
V_fixture_max= 3.400
|time   V(typ)   V(min)   V(max)
0s        2.627V     2.683V     2.548V
362ps     2.63V      2.685V     2.559V
452ps     2.643V     2.686V     3.076V
502ps     2.842V     2.686V     3.24V
562ps     3.074V     2.702V     3.322V
599ps     3.155V     2.803V     3.347V
686ps     3.241V     3.024V     3.376V
779ps     3.273V     3.126V     3.388V
1.326ns   3.299V     3.198V     3.4V
10ns      3.3V       3.2V       3.4V
[Falling Waveform]
R_fixture= 50.000
V_fixture= 3.300
V_fixture_min= 3.200
V_fixture_max= 3.400
|time   V(typ)   V(min)   V(max)
0s        3.3V       3.2V       3.4V
380ps     3.3V       3.2V       3.398V
483ps     3.289V     3.2V       3.103V
551ps     3.148V     3.201V     2.903V
597ps     3.03V      3.189V     2.818V
649ps     2.917V     3.115V     2.751V
840ps     2.734V     2.844V     2.63V
1.111ns   2.665V     2.731V     2.581V
1.871ns   2.642V     2.696V     2.564V
10ns      2.633V     2.689V     2.552V
[Falling Waveform]
R_fixture= 50.000
V_fixture= 0.0
V_fixture_min= 0.0
V_fixture_max= 0.0
|time   V(typ)   V(min)   V(max)
0s        718.7mV    534.6mV    935.3mV
374ps     718.2mV    534.4mV    934mV
426ps     718.7mV    534.3mV    765.2mV
471ps     712.5mV    534.2mV    455.3mV
505ps     641.9mV    534.2mV    263.7mV
542ps     524.5mV    536.1mV    159.4mV
631ps     166.6mV    462.6mV    56.47mV
801ps     28.69mV    95.99mV    9.496mV
1.281ns   405.5uV    1.667mV    152uV
10ns      23.81uV    32.87uV    20.91uV
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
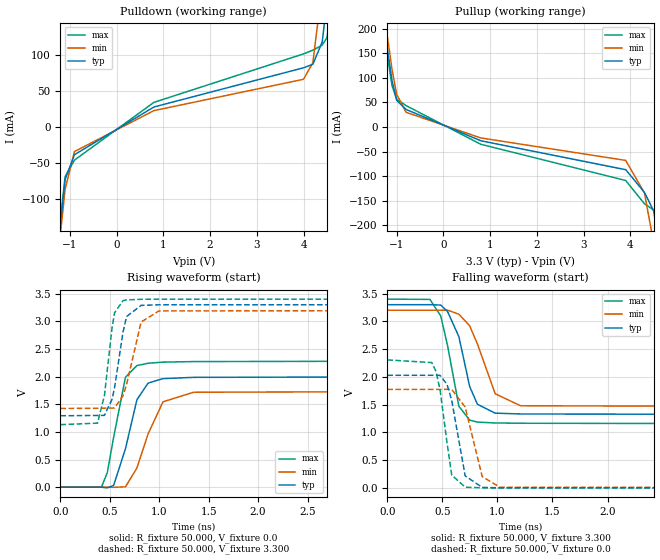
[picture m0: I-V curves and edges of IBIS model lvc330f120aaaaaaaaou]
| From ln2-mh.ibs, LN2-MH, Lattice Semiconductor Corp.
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|   Model lvc330f120aaaaaaaaou
[Model] lvc330f120aaaaaaaaou
Model_type Output
Polarity   Non-Inverting
Enable   Active-High
Vmeas =  1.650V
Cref =  0.0F
Rref =  1.000M
Vref =  0.0V
C_comp   5.000pF   4.000pF   5.500pF
[Temperature Range]   25.000   0.125k   -40.000
[Voltage Range]   3.300V   3.200V   3.400V
[C Comp Corner]
C_comp   5.000pF   4.000pF   5.500pF
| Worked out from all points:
|   slope of the pulldown table from 0 to 0.495 V, typ, clamps not added: 26.3 ohm
|   slope of the pullup table from 0 to 0.495 V, typ, clamps not added: 26.1 ohm
|   rising waveform, R_fixture 50.000, V_fixture 0.0: 20-80 % time 161ps typ, 207ps min, 133ps max; typ from 0 V to 2.02 V
|   rising waveform, R_fixture 50.000, V_fixture 3.300: 20-80 % time 107ps typ, 130ps min, 88.3ps max; typ from 1.29 V to 3.3 V
|   falling waveform, R_fixture 50.000, V_fixture 3.300: 20-80 % time 144ps typ, 183ps min, 121ps max; typ from 3.3 V to 1.3 V
|   falling waveform, R_fixture 50.000, V_fixture 0.0: 20-80 % time 104ps typ, 123ps min, 91.8ps max; typ from 2.03 V to 0 V
[Pulldown]
|Voltage   I(typ)   I(min)   I(max)
-3.3V     -1.89A     -1.89A     -1.887A
-1.3V     -196.4mA   -211.2mA   -189.4mA
-1.1V     -72.97mA   -86.55mA   -69.05mA
-900mV    -38.6mA    -34.27mA   -46.13mA
800mV     27.73mA    22.7mA     34.18mA
4V        82.27mA    66.28mA    101.6mA
4.2V      87.18mA    89.38mA    106.8mA
4.4V      118.1mA    194.6mA    113.8mA
4.5V      173.7mA    267.9mA    124.1mA
4.6V      246.1mA    347mA      166.3mA
4.7V      326.2mA    429.8mA    236mA
6.6V      2.055A     2.155A     1.956A
[Pullup]
|Voltage   I(typ)   I(min)   I(max)
-3.3V     2.051A     2.059A     2.045A
-1.3V     235.9mA    260mA      222.7mA
-1.2V     159.3mA    184.4mA    145.7mA
-1.1V     94.31mA    117.4mA    84mA
-1V       54.12mA    66.5mA     56.32mA
-800mV    35.59mA    29.83mA    43.44mA
800mV     -28.12mA   -22.4mA    -35.31mA
3.9V      -86.97mA   -68.07mA   -109mA
4.3V      -133mA     -134.3mA   -156.2mA
4.5V      -171.2mA   -236.5mA   -169.3mA
4.7V      -296.5mA   -380.8mA   -229.1mA
6.6V      -1.909A    -1.991A    -1.825A
[Ramp]
| variable   typ   min   max
dV/dt_r   1.211/0.161n   1.055/0.208n   1.380/0.133n
dV/dt_f   1.201/0.144n   1.058/0.184n   1.359/0.121n
R_load = 50.000
[Rising Waveform]
R_fixture= 50.000
V_fixture= 0.0
V_fixture_min= 0.0
V_fixture_max= 0.0
|time   V(typ)   V(min)   V(max)
0s        1.65uV     6.755uV    589nV
415ps     83.43uV    -333.5uV   1.713mV
474ps     -11.73mV   -200.7uV   263.5mV
538ps     31.88mV    -2.063mV   901.8mV
658ps     696.5mV    7.017mV    1.989V
774ps     1.583V     348.3mV    2.199V
887ps     1.882V     964.7mV    2.241V
1.038ns   1.963V     1.544V     2.261V
1.348ns   1.986V     1.717V     2.271V
10ns      2.018V     1.758V     2.3V
[Rising Waveform]
R_fixture= 50.000
V_fixture= 3.300
V_fixture_min= 3.200
V_fixture_max= 3.400
|time   V(typ)   V(min)   V(max)
0s        1.292V     1.424V     1.131V
375ps     1.297V     1.427V     1.158V
445ps     1.299V     1.429V     1.655V
522ps     1.588V     1.431V     2.879V
547ps     1.792V     1.432V     3.152V
633ps     2.802V     1.652V     3.372V
669ps     3.085V     1.855V     3.386V
816ps     3.287V     2.986V     3.397V
997ps     3.298V     3.187V     3.399V
10ns      3.3V       3.2V       3.4V
[Falling Waveform]
R_fixture= 50.000
V_fixture= 3.300
V_fixture_min= 3.200
V_fixture_max= 3.400
|time   V(typ)   V(min)   V(max)
0s        3.3V       3.2V       3.4V
387ps     3.3V       3.2V       3.395V
485ps     3.293V     3.2V       3.097V
547ps     3.177V     3.202V     2.564V
650ps     2.724V     3.128V     1.469V
748ps     1.826V     2.919V     1.221V
818ps     1.507V     2.594V     1.185V
980ps     1.346V     1.695V     1.169V
1.21ns    1.331V     1.479V     1.164V
10ns      1.299V     1.437V     1.134V
[Falling Waveform]
R_fixture= 50.000
V_fixture= 0.0
V_fixture_min= 0.0
V_fixture_max= 0.0
|time   V(typ)   V(min)   V(max)
0s        2.028V     1.774V     2.305V
404ps     2.028V     1.774V     2.257V
443ps     2.03V      1.774V     2.095V
479ps     2.026V     1.774V     1.764V
542ps     1.866V     1.775V     816.5mV
585ps     1.576V     1.774V     230.4mV
707ps     215.5mV    1.456V     11.91mV
862ps     8.414mV    202.1mV    882.2uV
1.024ns   742.4uV    10.5mV     198.4uV
10ns      15.74uV    25.59uV    11.54uV
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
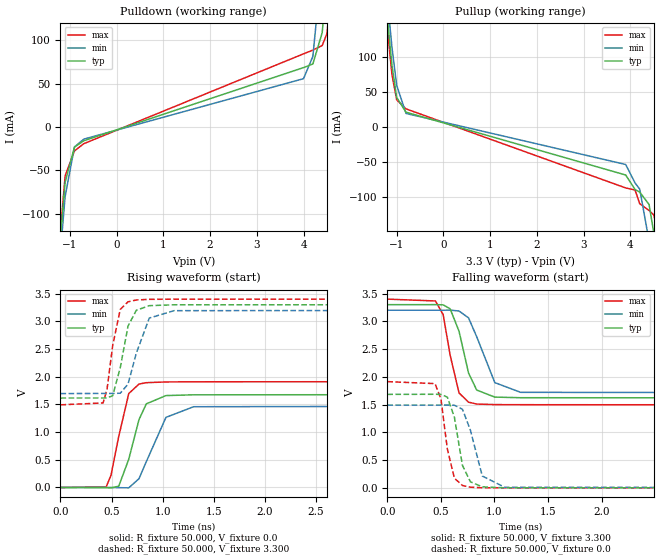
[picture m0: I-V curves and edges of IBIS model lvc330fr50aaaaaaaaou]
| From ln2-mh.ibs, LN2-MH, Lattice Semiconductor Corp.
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|   Model lvc330fr50aaaaaaaaou
[Model] lvc330fr50aaaaaaaaou
Model_type Output
Polarity   Non-Inverting
Enable   Active-High
Vmeas =  1.650V
Cref =  0.0F
Rref =  1.000M
Vref =  0.0V
C_comp   5.000pF   4.000pF   5.500pF
[Temperature Range]   25.000   0.125k   -40.000
[Voltage Range]   3.300V   3.200V   3.400V
[C Comp Corner]
C_comp   5.000pF   4.000pF   5.500pF
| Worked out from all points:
|   slope of the pulldown table from 0 to 0.495 V, typ, clamps not added: 49.2 ohm
|   slope of the pullup table from 0 to 0.495 V, typ, clamps not added: 49.2 ohm
|   rising waveform, R_fixture 50.000, V_fixture 0.0: 20-80 % time 149ps typ, 198ps min, 121ps max; typ from 0 V to 1.68 V
|   rising waveform, R_fixture 50.000, V_fixture 3.300: 20-80 % time 106ps typ, 133ps min, 85.1ps max; typ from 1.61 V to 3.3 V
|   falling waveform, R_fixture 50.000, V_fixture 3.300: 20-80 % time 127ps typ, 165ps min, 105ps max; typ from 3.3 V to 1.62 V
|   falling waveform, R_fixture 50.000, V_fixture 0.0: 20-80 % time 92.6ps typ, 111ps min, 81.1ps max; typ from 1.68 V to 0 V
[Pulldown]
|Voltage   I(typ)   I(min)   I(max)
-3.3V     -1.89A     -1.89A     -1.886A
-1.3V     -192.4mA   -207.9mA   -184.7mA
-1.1V     -63.87mA   -80.28mA   -56.56mA
-900mV    -23.31mA   -23.09mA   -27.65mA
-700mV    -15.96mA   -14.06mA   -19.31mA
4V        68.46mA    55.69mA    84.36mA
4.2V      72.61mA    81.37mA    88.62mA
4.4V      108.8mA    190.8mA    93.97mA
4.5V      168.1mA    265mA      107.5mA
4.6V      242.2mA    344.7mA    157.6mA
4.7V      323.1mA    427.8mA    230.5mA
6.6V      2.053A     2.154A     1.954A
[Pullup]
|Voltage   I(typ)   I(min)   I(max)
-3.3V     2.05A      2.058A     2.044A
-1.2V     155.1mA    181.3mA    140.3mA
-1.1V     87.3mA     112.8mA    73.9mA
-1V       41.81mA    59.32mA    38.57mA
-800mV    20.95mA    19.18mA    25.66mA
3.9V      -68.33mA   -53.38mA   -86.67mA
4.1V      -88.91mA   -79.68mA   -89.65mA
4.2V      -92.67mA   -88.38mA   -109.1mA
4.4V      -110.2mA   -162.4mA   -118.7mA
4.5V      -150.3mA   -225.9mA   -125.1mA
4.6V      -212.9mA   -297.3mA   -151.4mA
6.6V      -1.899A    -1.984A    -1.811A
[Ramp]
| variable   typ   min   max
dV/dt_r   1.009/0.149n   0.891/0.198n   1.148/0.121n
dV/dt_f   1.010/0.126n   0.900/0.165n   1.144/0.105n
R_load = 50.000
[Rising Waveform]
R_fixture= 50.000
V_fixture= 0.0
V_fixture_min= 0.0
V_fixture_max= 0.0
|time   V(typ)   V(min)   V(max)
0s        2.553uV    9.744uV    948.6nV
447ps     -2.554mV   -278.3uV   10.49mV
494ps     -6.635mV   -84.78uV   217.2mV
570ps     22.89mV    -3.602mV   920.2mV
668ps     509.3mV    -6.293mV   1.695V
768ps     1.224V     158.2mV    1.867V
840ps     1.51V      467.2mV    1.892V
1.032ns   1.659V     1.266V     1.905V
1.303ns   1.673V     1.458V     1.908V
10ns      1.682V     1.485V     1.913V
[Rising Waveform]
R_fixture= 50.000
V_fixture= 3.300
V_fixture_min= 3.200
V_fixture_max= 3.400
|time   V(typ)   V(min)   V(max)
0s        1.615V     1.696V     1.492V
417ps     1.616V     1.697V     1.526V
455ps     1.615V     1.697V     1.766V
511ps     1.656V     1.697V     2.563V
585ps     2.162V     1.702V     3.214V
661ps     2.913V     1.866V     3.352V
742ps     3.199V     2.425V     3.385V
869ps     3.282V     3.058V     3.396V
1.112ns   3.298V     3.192V     3.399V
10ns      3.3V       3.2V       3.4V
[Falling Waveform]
R_fixture= 50.000
V_fixture= 3.300
V_fixture_min= 3.200
V_fixture_max= 3.400
|time   V(typ)   V(min)   V(max)
0s        3.3V       3.2V       3.4V
449ps     3.301V     3.2V       3.367V
521ps     3.297V     3.2V       3.121V
586ps     3.226V     3.202V     2.392V
669ps     2.823V     3.186V     1.711V
758ps     2.068V     3.062V     1.543V
834ps     1.762V     2.722V     1.51V
1.003ns   1.635V     1.896V     1.5V
1.243ns   1.624V     1.721V     1.498V
10ns      1.617V     1.7V       1.493V
[Falling Waveform]
R_fixture= 50.000
V_fixture= 0.0
V_fixture_min= 0.0
V_fixture_max= 0.0
|time   V(typ)   V(min)   V(max)
0s        1.684V     1.491V     1.914V
445ps     1.686V     1.491V     1.878V
500ps     1.684V     1.491V     1.605V
560ps     1.634V     1.492V     700.2mV
626ps     1.272V     1.489V     174.1mV
701ps     405.3mV    1.416V     43.01mV
775ps     109.6mV    1.04V      11.83mV
886ps     18.27mV    213.4mV    2.106mV
1.095ns   997.1uV    10.19mV    250.2uV
10ns      22.49uV    33.83uV    17.38uV
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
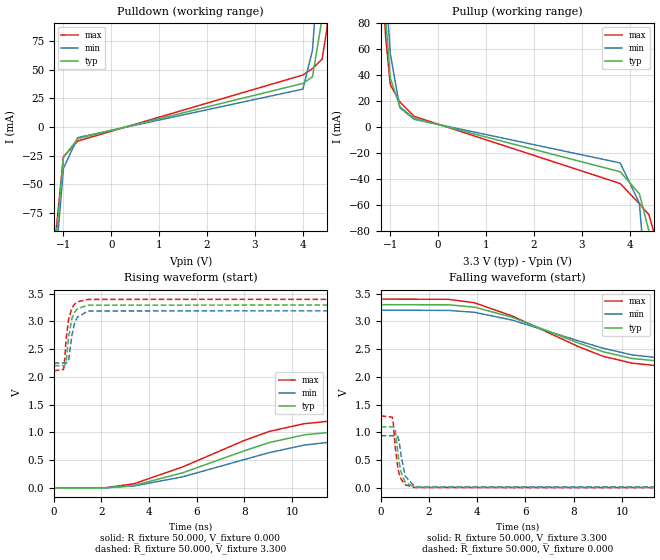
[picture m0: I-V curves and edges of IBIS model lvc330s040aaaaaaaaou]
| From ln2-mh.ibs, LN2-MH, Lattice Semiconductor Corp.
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|   Model lvc330s040aaaaaaaaou
[Model] lvc330s040aaaaaaaaou
Model_type Output
Polarity   Non-Inverting
Enable   Active-High
Vmeas =  1.650V
Cref =  0.0F
Rref =  1.000M
Vref =  0.0V
C_comp   5.000pF   4.000pF   5.500pF
[Temperature Range]   25.000   0.125k   -40.000
[Voltage Range]   3.300V   3.200V   3.400V
[C Comp Corner]
C_comp   5.000pF   4.000pF   5.500pF
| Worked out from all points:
|   slope of the pulldown table from 0 to 0.495 V, typ, clamps not added: 97.8 ohm
|   slope of the pullup table from 0 to 0.495 V, typ, clamps not added: 97.9 ohm
|   rising waveform, R_fixture 50.000, V_fixture 0.000: 20-80 % time 4.57ns typ, 4.96ns min, 4.5ns max; typ from 0 V to 1.1 V
|   rising waveform, R_fixture 50.000, V_fixture 3.300: 20-80 % time 225ps typ, 236ps min, 212ps max; typ from 2.2 V to 3.3 V
|   falling waveform, R_fixture 50.000, V_fixture 3.300: 20-80 % time 4.06ns typ, 4.36ns min, 4.04ns max; typ from 3.3 V to 2.2 V
|   falling waveform, R_fixture 50.000, V_fixture 0.000: 20-80 % time 228ps typ, 241ps min, 217ps max; typ from 1.1 V to 0 V
[Pulldown]
|Voltage   I(typ)   I(min)   I(max)
-3.3V     -1.889A    -1.889A    -1.885A
-1.3V     -190.6mA   -206.3mA   -182.7mA
-1.2V     -119.6mA   -137mA     -110.3mA
-1V       -26.58mA   -36.22mA   -26mA
-700mV    -10.17mA   -9.237mA   -12.29mA
4V        37.91mA    32.95mA    45.24mA
4.2V      43.71mA    66.9mA     50.86mA
4.4V      94.67mA    184.5mA    59.1mA
4.5V      159.6mA    260.2mA    84.98mA
4.6V      236.3mA    340.8mA    146.2mA
4.7V      318.5mA    424.5mA    223.2mA
6.6V      2.051A     2.152A     1.952A
[Pullup]
|Voltage   I(typ)   I(min)   I(max)
-3.3V     2.05A      2.058A     2.044A
-1.2V     153.6mA    179.9mA    138.5mA
-1.1V     84.88mA    110.9mA    70.67mA
-1V       37.66mA    56.5mA     32.62mA
-800mV    15.63mA    14.82mA    19.3mA
-500mV    6.55mA     5.856mA    8.142mA
3.8V      -34.58mA   -27.77mA   -43.65mA
4.2V      -51.54mA   -58.8mA    -59.21mA
4.4V      -80.52mA   -147.9mA   -67.74mA
4.5V      -132.3mA   -214.9mA   -80.66mA
4.6V      -200.2mA   -288.1mA   -126.3mA
6.6V      -1.893A    -1.98A     -1.804A
[Ramp]
| variable   typ   min   max
dV/dt_r   0.673/4.573n   0.576/4.958n   0.794/4.510n
dV/dt_f   0.673/4.068n   0.582/4.366n   0.790/4.048n
R_load = 50.000
[Rising Waveform]
R_fixture = 50.000
V_fixture = 0.000
V_fixture_min = 0.000
V_fixture_max = 0.000
|  time   V(typ)   V(min)   V(max)
0s        3.936uV    16.25uV    1.483uV
2.174ns   684.3uV    1.375mV    2.555mV
3.377ns   44.9mV     34.39mV    75.47mV
5.414ns   272.4mV    199.5mV    378.4mV
8.014ns   669.7mV    512mV      857.1mV
9.04ns    815.8mV    634.6mV    1.016V
10.51ns   954.6mV    770.3mV    1.156V
12.19ns   1.027V     852.3mV    1.228V
18.65ns   1.093V     932.5mV    1.29V
50ns      1.099V     940.1mV    1.297V
[Rising Waveform]
R_fixture = 50.000
V_fixture = 3.300
V_fixture_min = 3.200
V_fixture_max = 3.400
|  time   V(typ)   V(min)   V(max)
0s        2.201V     2.249V     2.109V
410ps     2.201V     2.25V      2.133V
446ps     2.201V     2.25V      2.261V
516ps     2.255V     2.25V      2.68V
619ps     2.713V     2.283V     3.035V
758ps     3.049V     2.746V     3.237V
859ps     3.156V     2.949V     3.305V
989ps     3.227V     3.074V     3.352V
1.433ns   3.292V     3.186V     3.395V
50ns      3.3V       3.2V       3.4V
[Falling Waveform]
R_fixture = 50.000
V_fixture = 3.300
V_fixture_min = 3.200
V_fixture_max = 3.400
|  time   V(typ)   V(min)   V(max)
0s        3.3V       3.2V       3.4V
2.8ns     3.298V     3.197V     3.397V
3.88ns    3.256V     3.163V     3.335V
5.455ns   3.073V     3.022V     3.096V
8.181ns   2.612V     2.651V     2.548V
9.213ns   2.453V     2.516V     2.371V
10.42ns   2.331V     2.395V     2.247V
12.19ns   2.256V     2.311V     2.167V
17.68ns   2.206V     2.256V     2.115V
50ns      2.201V     2.249V     2.109V
[Falling Waveform]
R_fixture = 50.000
V_fixture = 0.000
V_fixture_min = 0.000
V_fixture_max = 0.000
|  time   V(typ)   V(min)   V(max)
0s        1.099V     940.1mV    1.297V
480ps     1.099V     939.9mV    1.274V
521ps     1.099V     939.9mV    1.165V
604ps     1.052V     940.2mV    722.2mV
708ps     652mV      923.1mV    367.2mV
761ps     467.3mV    848.9mV    263.2mV
840ps     287.6mV    592.5mV    161.5mV
1.015ns   101.1mV    211.4mV    55.71mV
1.415ns   9.948mV    21.64mV    5.369mV
50ns      3.936uV    16.25uV    1.483uV
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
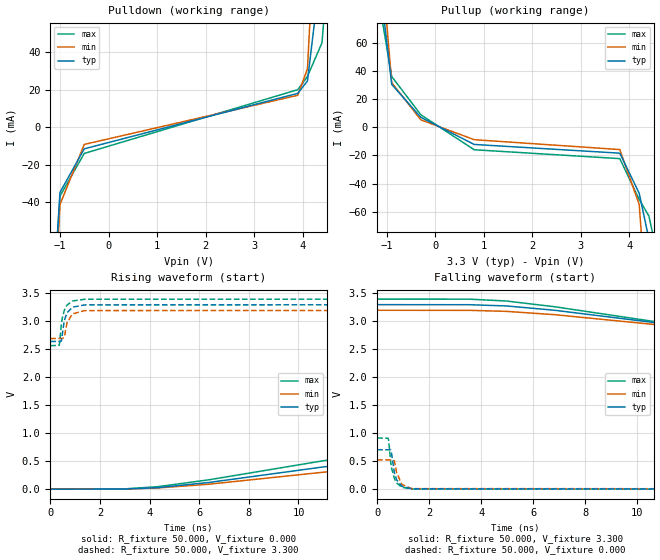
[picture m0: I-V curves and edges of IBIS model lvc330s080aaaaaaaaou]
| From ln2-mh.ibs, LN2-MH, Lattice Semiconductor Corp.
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|   Model lvc330s080aaaaaaaaou
[Model] lvc330s080aaaaaaaaou
Model_type Output
Polarity   Non-Inverting
Enable   Active-High
Vmeas =  1.650V
Cref =  0.0F
Rref =  1.000M
Vref =  0.0V
C_comp   5.000pF   4.000pF   5.500pF
[Temperature Range]   25.000   0.125k   -40.000
[Voltage Range]   3.300V   3.200V   3.400V
[C Comp Corner]
C_comp   5.000pF   4.000pF   5.500pF
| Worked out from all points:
|   slope of the pulldown table from 0 to 0.495 V, typ, clamps not added: 54.2 ohm
|   slope of the pullup table from 0 to 0.495 V, typ, clamps not added: 53.5 ohm
|   rising waveform, R_fixture 50.000, V_fixture 0.000: 20-80 % time 7.71ns typ, 7.45ns min, 8.19ns max; typ from 0 V to 0.705 V
|   rising waveform, R_fixture 50.000, V_fixture 3.300: 20-80 % time 206ps typ, 212ps min, 200ps max; typ from 2.64 V to 3.3 V
|   falling waveform, R_fixture 50.000, V_fixture 3.300: 20-80 % time 7.54ns typ, 7.25ns min, 7.97ns max; typ from 3.3 V to 2.64 V
|   falling waveform, R_fixture 50.000, V_fixture 0.000: 20-80 % time 204ps typ, 211ps min, 200ps max; typ from 0.705 V to 0 V
[Pulldown]
|Voltage   I(typ)   I(min)   I(max)
-3.3V     -1.888A    -1.889A    -1.884A
-1.3V     -192.7mA   -207.9mA   -185mA
-1.2V     -122.6mA   -139.3mA   -113.9mA
-1V       -34.79mA   -41.24mA   -36.74mA
-500mV    -11.57mA   -9.217mA   -14.02mA
3.9V      18.02mA    16.98mA    19.97mA
4.1V      24.62mA    31.12mA    27.04mA
4.4V      89.35mA    181.9mA    45.02mA
4.5V      156.5mA    258.2mA    77.93mA
4.6V      234.1mA    339.2mA    142.8mA
4.7V      316.8mA    423.2mA    221mA
6.6V      2.051A     2.152A     1.952A
[Pullup]
|Voltage   I(typ)   I(min)   I(max)
-3.3V     2.05A      2.058A     2.043A
-1.2V     156mA      181.6mA    141.7mA
-1.1V     89.07mA    113.5mA    76.66mA
-900mV    30.3mA     31.55mA    35.9mA
-300mV    6.959mA    5.173mA    8.774mA
800mV     -12.27mA   -8.89mA    -16.03mA
3.8V      -18.46mA   -15.9mA    -22.32mA
4.2V      -46.88mA   -54.83mA   -51.24mA
4.4V      -79.23mA   -146.5mA   -63.04mA
4.5V      -132mA     -213.9mA   -78.84mA
4.6V      -200.3mA   -287.5mA   -126.2mA
6.6V      -1.899A    -1.982A    -1.811A
[Ramp]
| variable   typ   min   max
dV/dt_r   0.433/7.714n   0.322/7.455n   0.563/8.209n
dV/dt_f   0.405/7.564n   0.311/7.285n   0.513/7.988n
R_load = 50.000
[Rising Waveform]
R_fixture = 50.000
V_fixture = 0.000
V_fixture_min = 0.000
V_fixture_max = 0.000
|  time   V(typ)   V(min)   V(max)
0s        3.3uV      16.16uV    1.165uV
2.95ns    1.776mV    2.406mV    3.576mV
4.319ns   26.9mV     21.13mV    43.71mV
6.359ns   117.9mV    87.15mV    165.6mV
10.96ns   395.2mV    301.4mV    505.5mV
13.64ns   530.3mV    402mV      674.7mV
16.45ns   626.5mV    471.5mV    800.6mV
19.65ns   686.3mV    510.9mV    885.9mV
23.25ns   698.1mV    518.3mV    910.6mV
50ns      704.6mV    524.2mV    916.9mV
[Rising Waveform]
R_fixture = 50.000
V_fixture = 3.300
V_fixture_min = 3.200
V_fixture_max = 3.400
|  time   V(typ)   V(min)   V(max)
0s        2.641V     2.693V     2.565V
361ps     2.643V     2.695V     2.573V
381ps     2.643V     2.695V     2.629V
448ps     2.649V     2.696V     2.959V
485ps     2.77V      2.696V     3.062V
564ps     3.013V     2.713V     3.196V
673ps     3.154V     2.974V     3.291V
894ps     3.255V     3.136V     3.366V
1.393ns   3.296V     3.194V     3.397V
50ns      3.3V       3.2V       3.4V
[Falling Waveform]
R_fixture = 50.000
V_fixture = 3.300
V_fixture_min = 3.200
V_fixture_max = 3.400
|  time   V(typ)   V(min)   V(max)
0s        3.3V       3.2V       3.4V
3.55ns    3.299V     3.198V     3.398V
4.972ns   3.277V     3.18V      3.365V
6.819ns   3.2V       3.121V     3.263V
11.43ns   2.936V     2.91V      2.945V
14.18ns   2.803V     2.807V     2.783V
16.85ns   2.714V     2.743V     2.67V
19.76ns   2.661V     2.709V     2.596V
23.78ns   2.646V     2.699V     2.57V
50ns      2.641V     2.693V     2.565V
[Falling Waveform]
R_fixture = 50.000
V_fixture = 0.000
V_fixture_min = 0.000
V_fixture_max = 0.000
|  time   V(typ)   V(min)   V(max)
0s        704.6mV    524.2mV    916.9mV
425ps     704mV      523.8mV    909.2mV
446ps     704.2mV    523.8mV    858.9mV
521ps     701.2mV    523.6mV    481.8mV
559ps     625.8mV    523.9mV    369.7mV
664ps     286.3mV    506.3mV    188.9mV
748ps     168.9mV    297.9mV    112.7mV
950ps     50.82mV    85.09mV    33.18mV
1.33ns    5.646mV    9.911mV    3.555mV
50ns      3.3uV      16.16uV    1.165uV
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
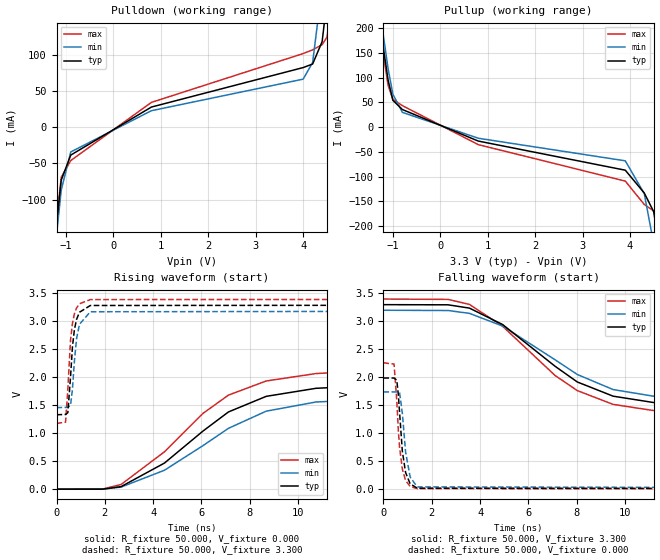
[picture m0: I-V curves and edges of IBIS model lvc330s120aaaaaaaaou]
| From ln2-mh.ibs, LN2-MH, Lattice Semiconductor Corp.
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|   Model lvc330s120aaaaaaaaou
[Model] lvc330s120aaaaaaaaou
Model_type Output
Polarity   Non-Inverting
Enable   Active-High
Vmeas =  1.650V
Cref =  0.0F
Rref =  1.000M
Vref =  0.0V
C_comp   5.000pF   4.000pF   5.500pF
[Temperature Range]   25.000   0.125k   -40.000
[Voltage Range]   3.300V   3.200V   3.400V
[C Comp Corner]
C_comp   5.000pF   4.000pF   5.500pF
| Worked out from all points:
|   slope of the pulldown table from 0 to 0.495 V, typ, clamps not added: 26.3 ohm
|   slope of the pullup table from 0 to 0.495 V, typ, clamps not added: 26.1 ohm
|   rising waveform, R_fixture 50.000, V_fixture 0.000: 20-80 % time 3.9ns typ, 4.15ns min, 3.8ns max; typ from 0 V to 1.99 V
|   rising waveform, R_fixture 50.000, V_fixture 3.300: 20-80 % time 217ps typ, 231ps min, 205ps max; typ from 1.33 V to 3.3 V
|   falling waveform, R_fixture 50.000, V_fixture 3.300: 20-80 % time 3.96ns typ, 4.09ns min, 3.93ns max; typ from 3.3 V to 1.33 V
|   falling waveform, R_fixture 50.000, V_fixture 0.000: 20-80 % time 233ps typ, 250ps min, 222ps max; typ from 1.99 V to 0 V
[Pulldown]
|Voltage   I(typ)   I(min)   I(max)
-3.3V     -1.89A     -1.89A     -1.887A
-1.3V     -196.4mA   -211.2mA   -189.4mA
-1.1V     -72.97mA   -86.55mA   -69.05mA
-900mV    -38.6mA    -34.27mA   -46.13mA
800mV     27.73mA    22.7mA     34.18mA
4V        82.27mA    66.28mA    101.6mA
4.2V      87.18mA    89.38mA    106.8mA
4.4V      118.1mA    194.6mA    113.8mA
4.5V      173.7mA    267.9mA    124.1mA
4.6V      246.1mA    347mA      166.3mA
4.7V      326.2mA    429.8mA    236mA
6.6V      2.055A     2.155A     1.956A
[Pullup]
|Voltage   I(typ)   I(min)   I(max)
-3.3V     2.051A     2.059A     2.045A
-1.3V     235.9mA    260mA      222.7mA
-1.2V     159.3mA    184.4mA    145.7mA
-1.1V     94.31mA    117.4mA    84mA
-1V       54.12mA    66.5mA     56.32mA
-800mV    35.59mA    29.83mA    43.44mA
800mV     -28.12mA   -22.4mA    -35.31mA
3.9V      -86.97mA   -68.06mA   -109mA
4.3V      -133mA     -134.3mA   -156.2mA
4.5V      -171.1mA   -236.5mA   -169.3mA
4.7V      -296.5mA   -380.8mA   -229.1mA
6.6V      -1.909A    -1.991A    -1.825A
[Ramp]
| variable   typ   min   max
dV/dt_r   1.220/3.907n   1.067/4.153n   1.386/3.808n
dV/dt_f   1.208/3.968n   1.069/4.104n   1.364/3.929n
R_load = 50.000
[Rising Waveform]
R_fixture = 50.000
V_fixture = 0.000
V_fixture_min = 0.000
V_fixture_max = 0.000
|  time   V(typ)   V(min)   V(max)
0s        1.629uV    6.667uV    580.9nV
1.927ns   1.104mV    1.631mV    3.612mV
2.676ns   45.53mV    37.23mV    84.08mV
4.472ns   467.1mV    338.5mV    668.6mV
6.067ns   1.039V     778.8mV    1.355V
7.122ns   1.381V     1.088V     1.682V
8.686ns   1.66V      1.395V     1.935V
10.75ns   1.804V     1.559V     2.068V
18.92ns   1.971V     1.718V     2.245V
50ns      1.988V     1.739V     2.26V
[Rising Waveform]
R_fixture = 50.000
V_fixture = 3.300
V_fixture_min = 3.200
V_fixture_max = 3.400
|  time   V(typ)   V(min)   V(max)
0s        1.331V     1.459V     1.175V
375ps     1.336V     1.462V     1.199V
469ps     1.369V     1.464V     1.793V
580ps     2.005V     1.497V     2.664V
659ps     2.544V     1.787V     2.965V
741ps     2.856V     2.293V     3.136V
831ps     3.039V     2.696V     3.241V
951ps     3.164V     2.948V     3.316V
1.4ns     3.285V     3.173V     3.391V
50ns      3.3V       3.2V       3.4V
[Falling Waveform]
R_fixture = 50.000
V_fixture = 3.300
V_fixture_min = 3.200
V_fixture_max = 3.400
|  time   V(typ)   V(min)   V(max)
0s        3.3V       3.2V       3.4V
2.68ns    3.297V     3.195V     3.394V
3.56ns    3.238V     3.144V     3.304V
4.93ns    2.945V     2.918V     2.914V
7.102ns   2.198V     2.314V     2.033V
8.022ns   1.917V     2.051V     1.763V
9.505ns   1.663V     1.781V     1.516V
11.85ns   1.504V     1.615V     1.362V
20.14ns   1.345V     1.477V     1.188V
50ns      1.331V     1.459V     1.175V
[Falling Waveform]
R_fixture = 50.000
V_fixture = 0.000
V_fixture_min = 0.000
V_fixture_max = 0.000
|  time   V(typ)   V(min)   V(max)
0s        1.988V     1.739V     2.26V
441ps     1.988V     1.739V     2.237V
554ps     1.949V     1.739V     1.579V
616ps     1.695V     1.739V     1.061V
671ps     1.362V     1.722V     740.1mV
784ps     676.8mV    1.357V     359.6mV
918ps     296.9mV    663.8mV    155.6mV
1.107ns   95.46mV    216.9mV    49.38mV
1.398ns   17.77mV    40.72mV    9.279mV
50ns      1.629uV    6.667uV    574.8nV
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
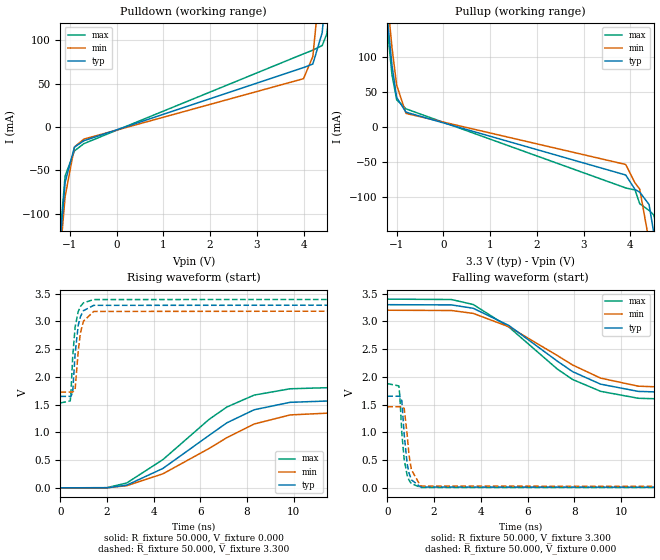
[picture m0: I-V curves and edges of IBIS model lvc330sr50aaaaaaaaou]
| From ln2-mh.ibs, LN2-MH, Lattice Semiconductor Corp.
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|   Model lvc330sr50aaaaaaaaou
[Model] lvc330sr50aaaaaaaaou
Model_type Output
Polarity   Non-Inverting
Enable   Active-High
Vmeas =  1.650V
Cref =  0.0F
Rref =  1.000M
Vref =  0.0V
C_comp   5.000pF   4.000pF   5.500pF
[Temperature Range]   25.000   0.125k   -40.000
[Voltage Range]   3.300V   3.200V   3.400V
[C Comp Corner]
C_comp   5.000pF   4.000pF   5.500pF
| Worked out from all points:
|   slope of the pulldown table from 0 to 0.495 V, typ, clamps not added: 49.2 ohm
|   slope of the pullup table from 0 to 0.495 V, typ, clamps not added: 49.2 ohm
|   rising waveform, R_fixture 50.000, V_fixture 0.000: 20-80 % time 3.48ns typ, 3.83ns min, 3.35ns max; typ from 0 V to 1.65 V
|   rising waveform, R_fixture 50.000, V_fixture 3.300: 20-80 % time 215ps typ, 227ps min, 204ps max; typ from 1.65 V to 3.3 V
|   falling waveform, R_fixture 50.000, V_fixture 3.300: 20-80 % time 3.4ns typ, 3.66ns min, 3.34ns max; typ from 3.3 V to 1.65 V
|   falling waveform, R_fixture 50.000, V_fixture 0.000: 20-80 % time 226ps typ, 240ps min, 215ps max; typ from 1.65 V to 0 V
[Pulldown]
|Voltage   I(typ)   I(min)   I(max)
-3.3V     -1.89A     -1.89A     -1.886A
-1.3V     -192.4mA   -207.9mA   -184.7mA
-1.1V     -63.87mA   -80.28mA   -56.56mA
-900mV    -23.31mA   -23.09mA   -27.65mA
-700mV    -15.96mA   -14.06mA   -19.31mA
4V        68.46mA    55.69mA    84.36mA
4.2V      72.61mA    81.37mA    88.62mA
4.4V      108.8mA    190.8mA    93.97mA
4.5V      168.1mA    265mA      107.5mA
4.6V      242.2mA    344.7mA    157.6mA
4.7V      323.1mA    427.8mA    230.5mA
6.6V      2.053A     2.154A     1.954A
[Pullup]
|Voltage   I(typ)   I(min)   I(max)
-3.3V     2.05A      2.058A     2.044A
-1.2V     155.1mA    181.3mA    140.3mA
-1.1V     87.3mA     112.8mA    73.9mA
-1V       41.81mA    59.32mA    38.57mA
-800mV    20.95mA    19.18mA    25.66mA
3.9V      -68.33mA   -53.38mA   -86.67mA
4.1V      -88.91mA   -79.68mA   -89.65mA
4.2V      -92.67mA   -88.37mA   -109.1mA
4.4V      -110.2mA   -162.4mA   -118.7mA
4.5V      -150.3mA   -225.9mA   -125.1mA
4.6V      -212.9mA   -297.3mA   -151.4mA
6.6V      -1.899A    -1.984A    -1.811A
[Ramp]
| variable   typ   min   max
dV/dt_r   1.011/3.476n   0.895/3.852n   1.149/3.348n
dV/dt_f   1.012/3.402n   0.903/3.659n   1.145/3.340n
R_load = 50.000
[Rising Waveform]
R_fixture = 50.000
V_fixture = 0.000
V_fixture_min = 0.000
V_fixture_max = 0.000
|  time   V(typ)   V(min)   V(max)
0s        2.504uV    9.557uV    930.2nV
1.995ns   1.186mV    1.768mV    3.907mV
2.845ns   49.25mV    39.39mV    88.35mV
4.395ns   350.2mV    253.3mV    509.6mV
6.368ns   944.1mV    708.6mV    1.232V
7.137ns   1.172V     905mV      1.457V
8.305ns   1.407V     1.15V      1.671V
9.847ns   1.541V     1.314V     1.785V
16.66ns   1.642V     1.449V     1.868V
50ns      1.651V     1.461V     1.877V
[Rising Waveform]
R_fixture = 50.000
V_fixture = 3.300
V_fixture_min = 3.200
V_fixture_max = 3.400
|  time   V(typ)   V(min)   V(max)
0s        1.648V     1.726V     1.53V
420ps     1.649V     1.726V     1.566V
452ps     1.647V     1.726V     1.73V
526ps     1.73V      1.726V     2.365V
629ps     2.419V     1.774V     2.898V
763ps     2.931V     2.467V     3.177V
857ps     3.084V     2.792V     3.267V
986ps     3.192V     3.002V     3.333V
1.428ns   3.288V     3.178V     3.392V
50ns      3.3V       3.2V       3.4V
[Falling Waveform]
R_fixture = 50.000
V_fixture = 3.300
V_fixture_min = 3.200
V_fixture_max = 3.400
|  time   V(typ)   V(min)   V(max)
0s        3.3V       3.2V       3.4V
2.741ns   3.296V     3.195V     3.393V
3.673ns   3.235V     3.143V     3.303V
5.203ns   2.924V     2.901V     2.895V
7.272ns   2.282V     2.383V     2.139V
7.92ns    2.094V     2.214V     1.953V
9.12ns    1.868V     1.977V     1.739V
10.73ns   1.738V     1.832V     1.614V
16.96ns   1.656V     1.735V     1.538V
50ns      1.648V     1.726V     1.53V
[Falling Waveform]
R_fixture = 50.000
V_fixture = 0.000
V_fixture_min = 0.000
V_fixture_max = 0.000
|  time   V(typ)   V(min)   V(max)
0s        1.651V     1.461V     1.877V
493ps     1.651V     1.461V     1.837V
533ps     1.651V     1.462V     1.668V
620ps     1.566V     1.462V     987.8mV
721ps     961.6mV    1.432V     511mV
845ps     440.9mV    969.7mV    233.2mV
926ps     268.9mV    598.9mV    141.3mV
1.028ns   145.5mV    326.7mV    75.91mV
1.424ns   14.58mV    33.38mV    7.606mV
50ns      2.504uV    9.557uV    929.7nV
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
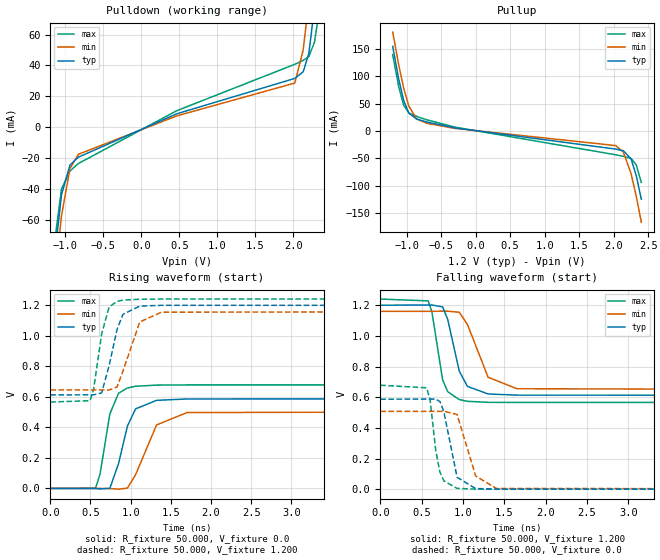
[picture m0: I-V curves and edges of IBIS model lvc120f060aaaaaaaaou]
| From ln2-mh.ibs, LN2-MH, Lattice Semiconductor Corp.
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|   Model lvc120f060aaaaaaaaou
[Model] lvc120f060aaaaaaaaou
Model_type Output
Polarity   Non-Inverting
Enable   Active-High
Vmeas =  0.600V
Cref =  0.0F
Rref =  1.000M
Vref =  0.0V
C_comp   5.000pF   4.000pF   5.500pF
[Temperature Range]   25.000   0.125k   -40.000
[Voltage Range]   1.200V   1.160V   1.240V
[C Comp Corner]
C_comp   5.000pF   4.000pF   5.500pF
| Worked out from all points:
|   slope of the pulldown table from 0 to 0.18 V, typ, clamps not added: 53.1 ohm
|   slope of the pullup table from 0 to 0.18 V, typ, clamps not added: 53.3 ohm
|   rising waveform, R_fixture 50.000, V_fixture 0.0: 20-80 % time 173ps typ, 238ps min, 134ps max; typ from 0 V to 0.587 V
|   rising waveform, R_fixture 50.000, V_fixture 1.200: 20-80 % time 152ps typ, 185ps min, 117ps max; typ from 0.612 V to 1.2 V
|   falling waveform, R_fixture 50.000, V_fixture 1.200: 20-80 % time 157ps typ, 214ps min, 120ps max; typ from 1.2 V to 0.612 V
|   falling waveform, R_fixture 50.000, V_fixture 0.0: 20-80 % time 118ps typ, 146ps min, 97ps max; typ from 0.587 V to 0 V
[Pulldown]
|Voltage   I(typ)   I(min)   I(max)
-1.2V     -121.4mA   -138.6mA   -112.5mA
-1.126V   -76.42mA   -93.57mA   -68mA
-1.052V   -43.76mA   -57.33mA   -40.03mA
-941mV    -24.61mA   -26.88mA   -28.42mA
-830mV    -19.46mA   -17.6mA    -23.59mA
465mV     8.656mA    7.285mA    10.67mA
2.019V    31.58mA    28.58mA    40.73mA
2.13V     35.91mA    50.13mA    43.28mA
2.204V    47.89mA    81.76mA    45.77mA
2.278V    77.57mA    125.1mA    55.07mA
2.315V    98.6mA     149.8mA    67.09mA
2.4V      156.2mA    211.4mA    113.9mA
[Pullup]
|Voltage   I(typ)   I(min)   I(max)
-1.2V     154.4mA    180.5mA    139.5mA
-1.115V   95.8mA     121.7mA    81.71mA
-1.041V   55.75mA    77.99mA    46.9mA
-967mV    32.67mA    45.61mA    33.03mA
-856mV    21.99mA    22.24mA    26.75mA
-708mV    16.47mA    14.07mA    20.53mA
-301mV    5.729mA    4.814mA    7.096mA
2.03V     -33.06mA   -26.61mA   -43.39mA
2.141V    -36.1mA    -38.88mA   -46.21mA
2.252V    -51.08mA   -77.9mA    -50.17mA
2.326V    -81.02mA   -118.6mA   -61.68mA
2.4V      -124.6mA   -166.4mA   -93.88mA
[Ramp]
| variable   typ   min   max
dV/dt_r   0.352/0.173n   0.304/0.239n   0.407/0.134n
dV/dt_f   0.353/0.157n   0.309/0.214n   0.405/0.120n
R_load = 50.000
[Rising Waveform]
R_fixture= 50.000
V_fixture= 0.0
V_fixture_min= 0.0
V_fixture_max= 0.0
|time   V(typ)   V(min)   V(max)
0s        29.11nV    1.236uV    3.133nV
563ps     -765.7uV   5.852uV    1.541mV
619ps     -3.68mV    53.9uV     92.94mV
741ps     822.9uV    -1.091mV   487.7mV
849ps     161.8mV    -4.921mV   622.8mV
960ps     408.7mV    2.085mV    657.9mV
1.061ns   520.8mV    89.64mV    669mV
1.322ns   576.7mV    415.7mV    676.5mV
1.701ns   585.8mV    496.7mV    677.8mV
10ns      586.9mV    507.4mV    678mV
[Rising Waveform]
R_fixture= 50.000
V_fixture= 1.200
V_fixture_min= 1.160
V_fixture_max= 1.240
|time   V(typ)   V(min)   V(max)
0s        612.5mV    644.8mV    565.7mV
495ps     612.8mV    645mV      574.3mV
539ps     612.6mV    645mV      648.5mV
639ps     625.6mV    645.1mV    1.012V
731ps     802mV      644.2mV    1.187V
830ps     1.04V      664.5mV    1.225V
904ps     1.14V      768mV      1.233V
1.113ns   1.194V     1.09V      1.239V
1.383ns   1.199V     1.154V     1.24V
10ns      1.2V       1.16V      1.24V
[Falling Waveform]
R_fixture= 50.000
V_fixture= 1.200
V_fixture_min= 1.160
V_fixture_max= 1.240
|time   V(typ)   V(min)   V(max)
0s        1.2V       1.16V      1.24V
580ps     1.201V     1.16V      1.228V
625ps     1.201V     1.16V      1.155V
754ps     1.189V     1.161V     713.6mV
815ps     1.109V     1.161V     636.3mV
955ps     770.8mV    1.154V     584.2mV
1.054ns   670.4mV    1.075V     573mV
1.304ns   621.1mV    730.2mV    566.5mV
1.654ns   613.3mV    655.1mV    565.7mV
10ns      612.5mV    644.8mV    565.6mV
[Falling Waveform]
R_fixture= 50.000
V_fixture= 0.0
V_fixture_min= 0.0
V_fixture_max= 0.0
|time   V(typ)   V(min)   V(max)
0s        586.9mV    507.4mV    677.9mV
562ps     587.5mV    507.4mV    661.1mV
603ps     588.1mV    507.4mV    580.2mV
671ps     586.8mV    507.3mV    251.5mV
721ps     572.1mV    507.8mV    112.7mV
769ps     505.8mV    508.3mV    54.28mV
929ps     77.52mV    487.2mV    5.063mV
1.154ns   3.968mV    85.65mV    318.9uV
1.404ns   327.6uV    4.691mV    51.42uV
10ns      6.14uV     11.85uV    3.093uV
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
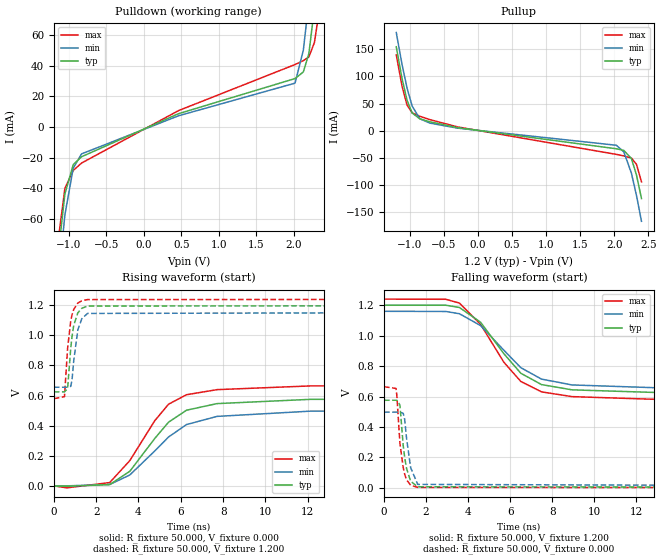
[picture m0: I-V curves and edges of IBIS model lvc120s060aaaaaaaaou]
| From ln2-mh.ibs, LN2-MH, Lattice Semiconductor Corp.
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|   Model lvc120s060aaaaaaaaou
[Model] lvc120s060aaaaaaaaou
Model_type Output
Polarity   Non-Inverting
Enable   Active-High
Vmeas =  0.600V
Cref =  0.0F
Rref =  1.000M
Vref =  0.0V
C_comp   5.000pF   4.000pF   5.500pF
[Temperature Range]   25.000   0.125k   -40.000
[Voltage Range]   1.200V   1.160V   1.240V
[C Comp Corner]
C_comp   5.000pF   4.000pF   5.500pF
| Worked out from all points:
|   slope of the pulldown table from 0 to 0.18 V, typ, clamps not added: 53.1 ohm
|   slope of the pullup table from 0 to 0.18 V, typ, clamps not added: 53.3 ohm
|   rising waveform, R_fixture 50.000, V_fixture 0.000: 20-80 % time 2.02ns typ, 2.3ns min, 1.91ns max; typ from 0 V to 0.575 V
|   rising waveform, R_fixture 50.000, V_fixture 1.200: 20-80 % time 267ps typ, 281ps min, 256ps max; typ from 0.624 V to 1.2 V
|   falling waveform, R_fixture 50.000, V_fixture 1.200: 20-80 % time 2.02ns typ, 2.19ns min, 1.99ns max; typ from 1.2 V to 0.624 V
|   falling waveform, R_fixture 50.000, V_fixture 0.000: 20-80 % time 284ps typ, 302ps min, 274ps max; typ from 0.575 V to 0 V
[Pulldown]
|Voltage   I(typ)   I(min)   I(max)
-1.2V     -121.4mA   -138.6mA   -112.5mA
-1.126V   -76.42mA   -93.57mA   -68mA
-1.052V   -43.76mA   -57.33mA   -40.03mA
-941mV    -24.61mA   -26.88mA   -28.42mA
-830mV    -19.46mA   -17.6mA    -23.59mA
465mV     8.656mA    7.285mA    10.67mA
2.019V    31.58mA    28.58mA    40.73mA
2.13V     35.91mA    50.13mA    43.28mA
2.204V    47.89mA    81.76mA    45.77mA
2.278V    77.57mA    125.1mA    55.07mA
2.315V    98.6mA     149.8mA    67.09mA
2.4V      156.2mA    211.4mA    113.9mA
[Pullup]
|Voltage   I(typ)   I(min)   I(max)
-1.2V     154.4mA    180.5mA    139.5mA
-1.115V   95.8mA     121.7mA    81.71mA
-1.041V   55.75mA    77.99mA    46.9mA
-967mV    32.67mA    45.61mA    33.03mA
-856mV    21.99mA    22.24mA    26.75mA
-708mV    16.47mA    14.07mA    20.53mA
-301mV    5.729mA    4.814mA    7.096mA
2.03V     -33.06mA   -26.61mA   -43.39mA
2.141V    -36.1mA    -38.88mA   -46.21mA
2.252V    -51.08mA   -77.9mA    -50.17mA
2.326V    -81.02mA   -118.6mA   -61.68mA
2.4V      -124.6mA   -166.4mA   -93.88mA
[Ramp]
| variable   typ   min   max
dV/dt_r   0.352/2.017n   0.304/2.305n   0.407/1.910n
dV/dt_f   0.353/2.021n   0.309/2.202n   0.405/2.007n
R_load = 50.000
[Rising Waveform]
R_fixture = 50.000
V_fixture = 0.000
V_fixture_min = 0.000
V_fixture_max = 0.000
|  time   V(typ)   V(min)   V(max)
0s        4.998uV    8.469uV    3.5uV
606ps     -2.676mV   52.41uV    -13.24mV
2.64ns    8.49mV     9.02mV     21.83mV
3.589ns   96.71mV    72.23mV    167.5mV
4.77ns    315mV      231.9mV    432.9mV
5.419ns   422.6mV    324.4mV    542.3mV
6.27ns    502.5mV    407.2mV    605.3mV
7.71ns    546.2mV    461.3mV    639mV
12.13ns   574.6mV    496.2mV    663.7mV
50ns      575.5mV    497.4mV    664.7mV
[Rising Waveform]
R_fixture = 50.000
V_fixture = 1.200
V_fixture_min = 1.160
V_fixture_max = 1.240
|  time   V(typ)   V(min)   V(max)
0s        624mV      654.9mV    578.9mV
503ps     624.3mV    655mV      592.6mV
651ps     646.1mV    655.2mV    913.2mV
799ps     913.4mV    660.7mV    1.096V
860ps     992.4mV    702.8mV    1.136V
940ps     1.065V     830.4mV    1.172V
1.134ns   1.149V     1.036V     1.214V
1.323ns   1.179V     1.11V      1.229V
1.593ns   1.194V     1.145V     1.237V
50ns      1.2V       1.16V      1.24V
[Falling Waveform]
R_fixture = 50.000
V_fixture = 1.200
V_fixture_min = 1.160
V_fixture_max = 1.240
|  time   V(typ)   V(min)   V(max)
0s        1.2V       1.16V      1.24V
2.939ns   1.2V       1.159V     1.239V
3.589ns   1.185V     1.144V     1.214V
4.595ns   1.088V     1.066V     1.074V
5.705ns   880.9mV    903.8mV    824.7mV
6.509ns   753mV      789.4mV    699.1mV
7.494ns   678.5mV    714.5mV    630.6mV
8.944ns   644mV      676.2mV    599.4mV
13.42ns   624.4mV    655.5mV    579.3mV
50ns      624mV      654.9mV    578.9mV
[Falling Waveform]
R_fixture = 50.000
V_fixture = 0.000
V_fixture_min = 0.000
V_fixture_max = 0.000
|  time   V(typ)   V(min)   V(max)
0s        575.5mV    497.4mV    664.7mV
570ps     575.7mV    497.4mV    653.1mV
610ps     575.6mV    497.4mV    607.8mV
757ps     545.1mV    497.5mV    291.8mV
915ps     275.8mV    489.3mV    132.3mV
985ps     198.4mV    448.4mV    88.56mV
1.073ns   127.5mV    324.6mV    52.88mV
1.267ns   43.34mV    132.9mV    17.31mV
1.604ns   7.087mV    22.85mV    3.061mV
50ns      4.998uV    8.469uV    3.5uV
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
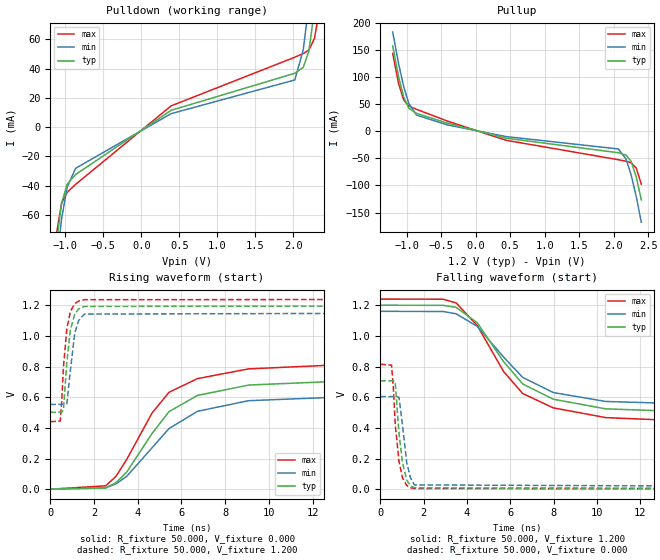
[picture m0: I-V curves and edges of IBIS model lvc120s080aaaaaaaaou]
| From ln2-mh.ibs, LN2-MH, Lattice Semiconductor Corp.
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|   Model lvc120s080aaaaaaaaou
[Model] lvc120s080aaaaaaaaou
Model_type Output
Polarity   Non-Inverting
Enable   Active-High
Vmeas =  0.600V
Cref =  0.0F
Rref =  1.000M
Vref =  0.0V
C_comp   5.000pF   4.000pF   5.500pF
[Temperature Range]   25.000   0.125k   -40.000
[Voltage Range]   1.200V   1.160V   1.240V
[C Comp Corner]
C_comp   5.000pF   4.000pF   5.500pF
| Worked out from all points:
|   slope of the pulldown table from 0 to 0.18 V, typ, clamps not added: 31.3 ohm
|   slope of the pullup table from 0 to 0.18 V, typ, clamps not added: 31.2 ohm
|   rising waveform, R_fixture 50.000, V_fixture 0.000: 20-80 % time 2.34ns typ, 2.54ns min, 2.25ns max; typ from 0 V to 0.707 V
|   rising waveform, R_fixture 50.000, V_fixture 1.200: 20-80 % time 270ps typ, 287ps min, 258ps max; typ from 0.501 V to 1.2 V
|   falling waveform, R_fixture 50.000, V_fixture 1.200: 20-80 % time 2.42ns typ, 2.52ns min, 2.4ns max; typ from 1.2 V to 0.501 V
|   falling waveform, R_fixture 50.000, V_fixture 0.000: 20-80 % time 293ps typ, 314ps min, 279ps max; typ from 0.707 V to 0 V
[Pulldown]
|Voltage   I(typ)   I(min)   I(max)
-1.2V     -125.5mA   -141.7mA   -117.5mA
-1.126V   -82.18mA   -97.71mA   -75.64mA
-1.052V   -52.35mA   -62.95mA   -52.09mA
-978mV    -38.99mA   -41.1mA    -44.58mA
-867mV    -32.34mA   -28.12mA   -39.09mA
391mV     11.49mA    9.231mA    14.53mA
2.019V    36.8mA     32.22mA    47.75mA
2.13V     40.84mA    52.82mA    50.28mA
2.204V    51.83mA    83.7mA     52.6mA
2.278V    80.16mA    126.5mA    60.63mA
2.315V    100.7mA    151.1mA    71.46mA
2.4V      157.6mA    212.3mA    116.2mA
[Pullup]
|Voltage   I(typ)   I(min)   I(max)
-1.2V     157.2mA    182.6mA    143.1mA
-1.115V   100.2mA    124.6mA    87.96mA
-1.041V   62.63mA    82.08mA    57.47mA
-967mV    42.4mA     51.3mA     46.5mA
-856mV    32.8mA     29.67mA    40.24mA
-412mV    14.79mA    11.57mA    18.71mA
439mV     -12.88mA   -9.955mA   -16.74mA
2.067V    -39.79mA   -32.82mA   -52.62mA
2.178V    -44.03mA   -51.4mA    -55.48mA
2.252V    -55.53mA   -80.14mA   -58.17mA
2.326V    -84.03mA   -120.3mA   -67.92mA
2.4V      -126.7mA   -167.8mA   -97.74mA
[Ramp]
| variable   typ   min   max
dV/dt_r   0.433/2.344n   0.370/2.544n   0.499/2.253n
dV/dt_f   0.428/2.418n   0.372/2.519n   0.490/2.403n
R_load = 50.000
[Rising Waveform]
R_fixture = 50.000
V_fixture = 0.000
V_fixture_min = 0.000
V_fixture_max = 0.000
|  time   V(typ)   V(min)   V(max)
0s        49.63uV    47.32uV    45.12uV
2.539ns   7.971mV    8.643mV    21.71mV
3.014ns   43.37mV    35.43mV    85.1mV
3.503ns   112.9mV    84.29mV    195.5mV
4.66ns    363.9mV    270.3mV    497.4mV
5.434ns   506mV      395.7mV    632.1mV
6.734ns   611.4mV    507.9mV    721.2mV
9.074ns   679.1mV    577.2mV    784.6mV
13.67ns   706.7mV    603.2mV    814.3mV
50ns      707.1mV    603.8mV    814.8mV
[Rising Waveform]
R_fixture = 50.000
V_fixture = 1.200
V_fixture_min = 1.160
V_fixture_max = 1.240
|  time   V(typ)   V(min)   V(max)
0s        501.3mV    552.8mV    440.2mV
454ps     502.2mV    553.3mV    443.8mV
521ps     502.1mV    553.4mV    565.9mV
602ps     518.3mV    553.6mV    795.9mV
757ps     825.4mV    556mV      1.045V
919ps     1.039V     774.8mV    1.159V
1.12ns    1.142V     1.018V     1.21V
1.3ns     1.176V     1.101V     1.227V
1.564ns   1.192V     1.142V     1.236V
50ns      1.2V       1.16V      1.24V
[Falling Waveform]
R_fixture = 50.000
V_fixture = 1.200
V_fixture_min = 1.160
V_fixture_max = 1.240
|  time   V(typ)   V(min)   V(max)
0s        1.2V       1.16V      1.24V
2.898ns   1.199V     1.159V     1.239V
3.502ns   1.186V     1.144V     1.215V
4.477ns   1.085V     1.062V     1.067V
5.692ns   831.9mV    861.9mV    767.7mV
6.572ns   686.7mV    729.3mV    624mV
7.986ns   586.8mV    630.2mV    530.4mV
10.41ns   523.9mV    572.1mV    466.7mV
14.83ns   501.9mV    553.6mV    440.8mV
50ns      501.3mV    552.8mV    440.2mV
[Falling Waveform]
R_fixture = 50.000
V_fixture = 0.000
V_fixture_min = 0.000
V_fixture_max = 0.000
|  time   V(typ)   V(min)   V(max)
0s        707.1mV    603.8mV    814.8mV
521ps     706.7mV    603.8mV    808.8mV
605ps     707.2mV    603.7mV    656.9mV
691ps     689.7mV    603.5mV    420.1mV
865ps     364.4mV    599.6mV    181.4mV
1.026ns   171.6mV    416.7mV    74.01mV
1.222ns   59.45mV    173mV      23.8mV
1.392ns   23.18mV    74.2mV     9.336mV
1.578ns   8.719mV    27.8mV     3.779mV
50ns      49.63uV    47.32uV    45.12uV
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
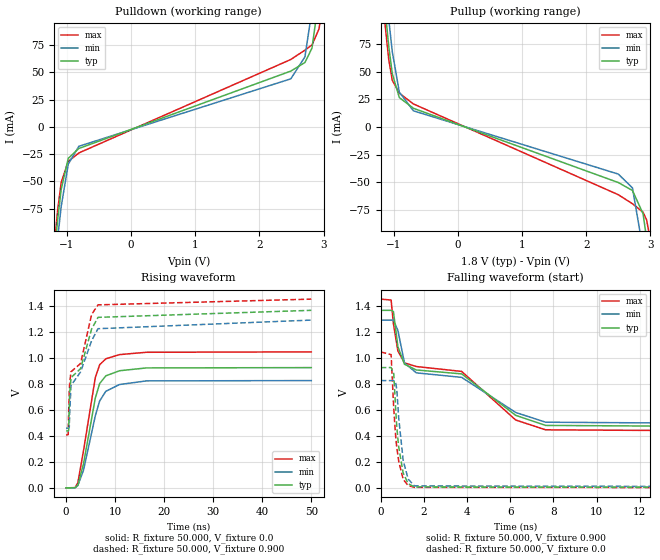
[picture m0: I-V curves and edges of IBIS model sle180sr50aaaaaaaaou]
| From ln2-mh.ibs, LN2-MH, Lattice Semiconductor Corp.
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|   Model sle180sr50aaaaaaaaou
[Model] sle180sr50aaaaaaaaou
Model_type Output
Polarity   Non-Inverting
Enable   Active-High
Vmeas =  0.900V
Cref =  3.000pF
Rref =  50.000
Vref =  0.900V
C_comp   5.000pF   4.000pF   5.500pF
[Temperature Range]   25.000   0.125k   -40.000
[Voltage Range]   1.800V   1.750V   1.850V
[C Comp Corner]
C_comp   5.000pF   4.000pF   5.500pF
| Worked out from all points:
|   slope of the pulldown table from 0 to 0.27 V, typ, clamps not added: 49.2 ohm
|   slope of the pullup table from 0 to 0.27 V, typ, clamps not added: 49.2 ohm
|   rising waveform, R_fixture 50.000, V_fixture 0.0: 20-80 % time 2.73ns typ, 3.02ns min, 2.62ns max; typ from 0 V to 0.923 V
|   rising waveform, R_fixture 50.000, V_fixture 0.900: 20-80 % time 4.28ns typ, 4.37ns min, 4.11ns max; typ from 0.437 V to 1.36 V
|   falling waveform, R_fixture 50.000, V_fixture 0.900: 20-80 % time 5.04ns typ, 4.99ns min, 5.02ns max; typ from 1.36 V to 0.437 V
|   falling waveform, R_fixture 50.000, V_fixture 0.0: 20-80 % time 295ps typ, 308ps min, 285ps max; typ from 0.923 V to 0 V
[Pulldown]
|Voltage   I(typ)   I(min)   I(max)
-1.8V     -596mA     -603.6mA   -592.5mA
-1.195V   -118.6mA   -135.8mA   -109.7mA
-1.14V    -84.81mA   -102.1mA   -76.16mA
-1.085V   -57.12mA   -72.8mA    -50.75mA
-975mV    -28.76mA   -34.06mA   -31.57mA
-810mV    -19.75mA   -17.75mA   -23.83mA
2.49V     51.18mA    44.08mA    61.82mA
2.71V     59.04mA    64.25mA    70.37mA
2.82V     72.29mA    107.1mA    75.18mA
2.93V     119mA      174.8mA    89.91mA
2.985V    154.1mA    214.1mA    112.6mA
3.6V      670.6mA    731.8mA    617mA
[Pullup]
|Voltage   I(typ)   I(min)   I(max)
-1.8V     667.2mA    684.4mA    658mA
-1.13V    106mA      132.1mA    91.59mA
-1.075V   73.12mA    97.61mA    61.16mA
-1.02V    48.26mA    68.32mA    42.26mA
-910mV    26.56mA    31.42mA    30.55mA
-690mV    16.86mA    14.58mA    20.78mA
2.5V      -50.34mA   -42.68mA   -61.37mA
2.72V     -57.55mA   -55.19mA   -69.5mA
2.885V    -78.55mA   -111.1mA   -77.19mA
2.94V     -100.9mA   -142.4mA   -84.11mA
2.995V    -131.1mA   -177.5mA   -101.1mA
3.6V      -601.3mA   -649.3mA   -557.2mA
[Ramp]
| variable   typ   min   max
dV/dt_r   0.554/2.733n   0.494/3.024n   0.627/2.625n
dV/dt_f   0.554/2.772n   0.498/2.933n   0.625/2.758n
R_load = 50.000
[Rising Waveform]
R_fixture= 50.000
V_fixture= 0.0
V_fixture_min= 0.0
V_fixture_max= 0.0
|time   V(typ)   V(min)   V(max)
0s        369.3nV    3.503uV    105.9nV
1.828ns   581.6uV    948.1uV    1.836mV
2.396ns   19.52mV    18.09mV    38.76mV
3.561ns   187mV      136.8mV    287.2mV
5.968ns   690.7mV    554.7mV    848.7mV
6.85ns    800.9mV    667.5mV    945.1mV
8.1ns     859.9mV    741.6mV    991.1mV
10.9ns    899.2mV    793.4mV    1.023V
16.37ns   920.8mV    821.2mV    1.041V
50ns      923.2mV    823.7mV    1.044V
[Rising Waveform]
R_fixture= 50.000
V_fixture= 0.900
V_fixture_min= 0.874
V_fixture_max= 0.928
|time   V(typ)   V(min)   V(max)
0s        437.4mV    458.2mV    405.1mV
433ps     437mV      458.3mV    408.5mV
526ps     441.6mV    458.2mV    586.1mV
651ps     636.5mV    466.8mV    745.2mV
731ps     719mV      571mV      802.5mV
1.001ns   846.1mV    785.6mV    891mV
2.95ns    915.3mV    889.8mV    954.8mV
5.201ns   1.219V     1.129V     1.331V
6.511ns   1.309V     1.222V     1.405V
50ns      1.363V     1.288V     1.449V
[Falling Waveform]
R_fixture= 50.000
V_fixture= 0.900
V_fixture_min= 0.874
V_fixture_max= 0.928
|time   V(typ)   V(min)   V(max)
0s        1.363V     1.288V     1.449V
483ps     1.363V     1.288V     1.442V
589ps     1.354V     1.289V     1.26V
796ps     1.084V     1.208V     1.051V
1.102ns   949mV      959.1mV    959.8mV
1.651ns   905.1mV    882.9mV    931.4mV
3.75ns    875mV      848.4mV    894mV
6.252ns   556.9mV    578.9mV    521mV
7.64ns    479.4mV    504mV      445.6mV
50ns      437.4mV    458.2mV    405.1mV
[Falling Waveform]
R_fixture= 50.000
V_fixture= 0.0
V_fixture_min= 0.0
V_fixture_max= 0.0
|time   V(typ)   V(min)   V(max)
0s        923.2mV    823.7mV    1.044V
482ps     923.8mV    823.7mV    1.023V
604ps     877.4mV    824.5mV    609.1mV
694ps     602.3mV    808.4mV    391.9mV
746ps     467.8mV    754.6mV    307.4mV
831ps     315.1mV    543mV      206.8mV
1.041ns   114.8mV    209.7mV    65.53mV
1.272ns   31.77mV    67.85mV    17.39mV
1.562ns   6.858mV    14.88mV    3.865mV
50ns      1.354uV    4.189uV    831.9nV
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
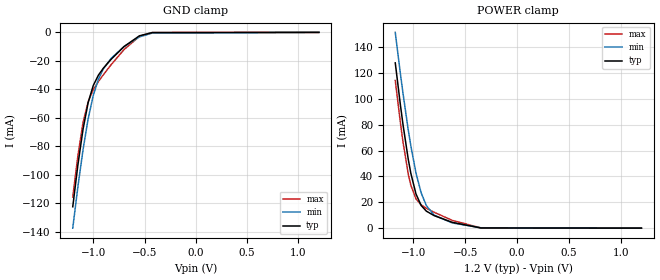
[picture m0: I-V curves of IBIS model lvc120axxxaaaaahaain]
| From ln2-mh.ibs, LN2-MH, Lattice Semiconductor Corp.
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|   Model lvc120axxxaaaaahaain
[Model] lvc120axxxaaaaahaain
Model_type Input
Polarity   Non-Inverting
Enable   Active-High
Vinl =  0.420V
Vinh =  0.780V
C_comp   2.000pF   1.500pF   2.500pF
[Temperature Range]   25.000   0.125k   -40.000
[Voltage Range]   1.200V   1.160V   1.240V
[C Comp Corner]
C_comp   2.000pF   1.500pF   2.500pF
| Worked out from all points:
|   GND clamp passes 1 mA (typ) near -0.50 V on its own axis
|   POWER clamp passes 1 mA (typ) near -0.45 V on its own axis
[GND_clamp]
|Voltage   I(typ)   I(min)   I(max)
-1.2V     -122.3mA   -137.3mA   -115.6mA
-1.15V    -92.96mA   -108.3mA   -86.45mA
-1.1V     -68.03mA   -82.39mA   -63.38mA
-1.05V    -49.27mA   -60.71mA   -48.52mA
-1V       -37.26mA   -44.16mA   -40.17mA
-950mV    -30.01mA   -32.79mA   -34.49mA
-900mV    -24.97mA   -25.37mA   -29.56mA
-825mV    -18.8mA    -18.19mA   -22.61mA
-700mV    -9.952mA   -9.962mA   -12.07mA
-550mV    -2.408mA   -3.159mA   -2.79mA
-425mV    -153.5uA   -502uA     -104.5uA
1.2V      0A         0A         0A
[POWER_clamp]
|Voltage   I(typ)   I(min)   I(max)
-1.175V   127.9mA    151.5mA    114.3mA
-1.125V   95.1mA     119.3mA    81.28mA
-1.1V     80mA       104.1mA    66.45mA
-1.05V    53.45mA    76.24mA    42.06mA
-1.025V   42.52mA    63.79mA    33.25mA
-975mV    26.41mA    42.63mA    22.64mA
-925mV    17.53mA    27.24mA    17.96mA
-875mV    13.14mA    17.46mA    15.36mA
-800mV    9.702mA    10.06mA    12.29mA
-625mV    4.476mA    4.013mA    6.017mA
-350mV    147.7uA    296.5uA    176.7uA
1.2V      0A         0A         0A
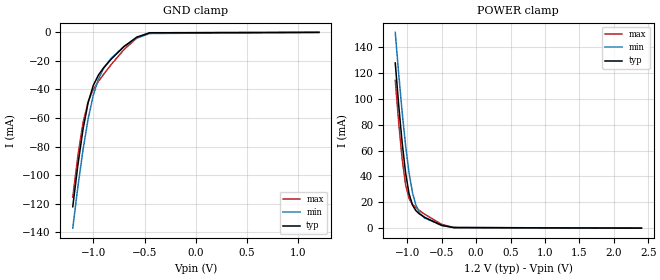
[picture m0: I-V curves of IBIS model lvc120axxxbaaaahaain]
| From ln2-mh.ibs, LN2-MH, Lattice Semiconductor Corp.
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|   Model lvc120axxxbaaaahaain
[Model] lvc120axxxbaaaahaain
Model_type Input
Polarity   Non-Inverting
Enable   Active-High
Vinl =  0.420V
Vinh =  0.780V
C_comp   2.000pF   1.500pF   2.500pF
[Temperature Range]   25.000   0.125k   -40.000
[Voltage Range]   1.200V   1.160V   1.240V
[C Comp Corner]
C_comp   2.000pF   1.500pF   2.500pF
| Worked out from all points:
|   GND clamp passes 1 mA (typ) near -0.50 V on its own axis
|   POWER clamp passes 1 mA (typ) near -0.43 V on its own axis
[GND_clamp]
|Voltage   I(typ)   I(min)   I(max)
-1.2V     -122.2mA   -137.2mA   -115.5mA
-1.15V    -92.87mA   -108.2mA   -86.36mA
-1.1V     -67.94mA   -82.3mA    -63.29mA
-1.05V    -49.18mA   -60.62mA   -48.44mA
-1V       -37.17mA   -44.08mA   -40.09mA
-950mV    -29.93mA   -32.7mA    -34.41mA
-900mV    -24.89mA   -25.29mA   -29.48mA
-825mV    -18.72mA   -18.11mA   -22.53mA
-700mV    -9.885mA   -9.895mA   -12mA
-575mV    -3.29mA    -3.992mA   -3.897mA
-450mV    -308.5uA   -780uA     -256.3uA
1.2V      0A         0A         0A
[POWER_clamp]
|Voltage   I(typ)   I(min)   I(max)
-1.175V   127.9mA    151.6mA    114.4mA
-1.125V   95.2mA     119.4mA    81.41mA
-1.075V   66.17mA    89.85mA    53.4mA
-1.025V   42.7mA     63.91mA    33.48mA
-975mV    26.64mA    42.78mA    22.93mA
-925mV    17.79mA    27.41mA    18.29mA
-875mV    13.42mA    17.66mA    15.69mA
-825mV    10.95mA    12.07mA    13.61mA
-750mV    8.323mA    7.791mA    10.74mA
-500mV    2.04mA     1.98mA     2.782mA
-325mV    310.3uA    373.2uA    366.8uA
2.4V      -105uA     -106.2uA   -106.1uA
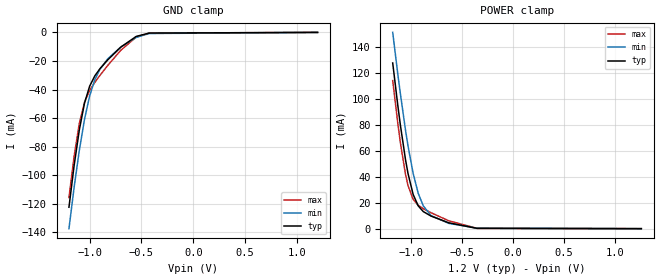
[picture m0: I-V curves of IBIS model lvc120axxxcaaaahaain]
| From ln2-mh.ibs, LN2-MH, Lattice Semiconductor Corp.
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|   Model lvc120axxxcaaaahaain
[Model] lvc120axxxcaaaahaain
Model_type Input
Polarity   Non-Inverting
Enable   Active-High
Vinl =  0.420V
Vinh =  0.780V
C_comp   2.000pF   1.500pF   2.500pF
[Temperature Range]   25.000   0.125k   -40.000
[Voltage Range]   1.200V   1.160V   1.240V
[C Comp Corner]
C_comp   2.000pF   1.500pF   2.500pF
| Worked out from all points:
|   GND clamp passes 1 mA (typ) near -0.48 V on its own axis
|   POWER clamp passes 1 mA (typ) near -0.45 V on its own axis
[GND_clamp]
|Voltage   I(typ)   I(min)   I(max)
-1.2V     -122.4mA   -137.4mA   -115.7mA
-1.15V    -93.15mA   -108.4mA   -86.68mA
-1.1V     -68.26mA   -82.56mA   -63.69mA
-1.05V    -49.56mA   -60.91mA   -48.91mA
-1V       -37.6mA    -44.4mA    -40.61mA
-950mV    -30.39mA   -33.06mA   -34.94mA
-900mV    -25.36mA   -25.66mA   -30.02mA
-825mV    -19.19mA   -18.49mA   -23.08mA
-700mV    -10.35mA   -10.27mA   -12.54mA
-550mV    -2.791mA   -3.463mA   -3.253mA
-425mV    -485.3uA   -772.4uA   -506.7uA
1.2V      0A         0A         0A
[POWER_clamp]
|Voltage   I(typ)   I(min)   I(max)
-1.175V   127.9mA    151.5mA    114.3mA
-1.125V   95.1mA     119.3mA    81.29mA
-1.1V     80.01mA    104.2mA    66.46mA
-1.05V    53.46mA    76.26mA    42.07mA
-1.025V   42.54mA    63.8mA     33.26mA
-975mV    26.43mA    42.65mA    22.66mA
-925mV    17.55mA    27.26mA    17.98mA
-875mV    13.16mA    17.49mA    15.38mA
-800mV    9.729mA    10.09mA    12.32mA
-625mV    4.511mA    4.051mA    6.05mA
-350mV    232.9uA    372.5uA    262.7uA
1.26V     0A         0A         0A
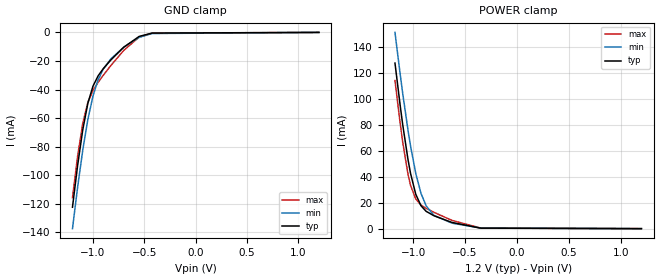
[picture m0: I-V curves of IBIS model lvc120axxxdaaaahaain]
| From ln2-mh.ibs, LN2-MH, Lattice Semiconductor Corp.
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|   Model lvc120axxxdaaaahaain
[Model] lvc120axxxdaaaahaain
Model_type Input
Polarity   Non-Inverting
Enable   Active-High
Vinl =  0.420V
Vinh =  0.780V
C_comp   2.000pF   1.500pF   2.500pF
[Temperature Range]   25.000   0.125k   -40.000
[Voltage Range]   1.200V   1.160V   1.240V
[C Comp Corner]
C_comp   2.000pF   1.500pF   2.500pF
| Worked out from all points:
|   GND clamp passes 1 mA (typ) near -0.48 V on its own axis
|   POWER clamp passes 1 mA (typ) near -0.43 V on its own axis
[GND_clamp]
|Voltage   I(typ)   I(min)   I(max)
-1.2V     -122.4mA   -137.4mA   -115.7mA
-1.15V    -93.15mA   -108.4mA   -86.68mA
-1.1V     -68.26mA   -82.56mA   -63.69mA
-1.05V    -49.56mA   -60.91mA   -48.91mA
-1V       -37.6mA    -44.4mA    -40.61mA
-950mV    -30.39mA   -33.06mA   -34.94mA
-900mV    -25.36mA   -25.66mA   -30.02mA
-825mV    -19.19mA   -18.49mA   -23.08mA
-700mV    -10.35mA   -10.27mA   -12.54mA
-550mV    -2.791mA   -3.463mA   -3.253mA
-425mV    -485.3uA   -772.4uA   -506.7uA
1.2V      -845nA     5.24uA     -30.51uA
[POWER_clamp]
|Voltage   I(typ)   I(min)   I(max)
-1.175V   127.9mA    151.6mA    114.4mA
-1.125V   95.2mA     119.4mA    81.41mA
-1.1V     80.12mA    104.2mA    66.6mA
-1.05V    53.6mA     76.35mA    42.26mA
-1.025V   42.7mA     63.91mA    33.48mA
-975mV    26.64mA    42.78mA    22.93mA
-925mV    17.79mA    27.41mA    18.29mA
-875mV    13.42mA    17.66mA    15.69mA
-800mV    9.995mA    10.28mA    12.63mA
-625mV    4.774mA    4.24mA     6.369mA
-350mV    398.5uA    489.6uA    483.6uA
1.2V      0A         0A         28.76uA
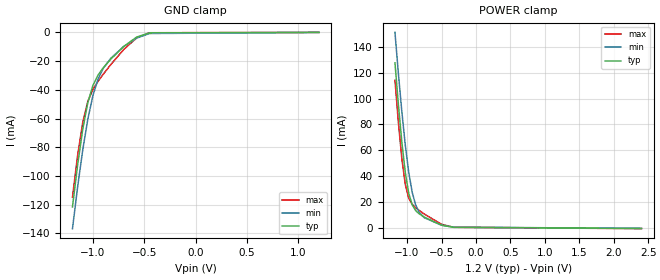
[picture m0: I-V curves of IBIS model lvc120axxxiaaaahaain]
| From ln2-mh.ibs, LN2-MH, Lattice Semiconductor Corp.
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|   Model lvc120axxxiaaaahaain
[Model] lvc120axxxiaaaahaain
Model_type Input
Polarity   Non-Inverting
Enable   Active-High
Vinl =  0.420V
Vinh =  0.780V
C_comp   2.000pF   1.500pF   2.500pF
[Temperature Range]   25.000   0.125k   -40.000
[Voltage Range]   1.200V   1.160V   1.240V
[C Comp Corner]
C_comp   2.000pF   1.500pF   2.500pF
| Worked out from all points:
|   GND clamp passes 1 mA (typ) near -0.50 V on its own axis
|   POWER clamp passes 1 mA (typ) near -0.44 V on its own axis
[GND_clamp]
|Voltage   I(typ)   I(min)   I(max)
-1.2V     -121.6mA   -136.7mA   -114.8mA
-1.15V    -92.34mA   -107.7mA   -85.69mA
-1.1V     -67.45mA   -81.88mA   -62.68mA
-1.05V    -48.74mA   -60.24mA   -47.9mA
-1V       -36.78mA   -43.73mA   -39.61mA
-950mV    -29.6mA    -32.4mA    -33.99mA
-900mV    -24.6mA    -25.02mA   -29.11mA
-825mV    -18.49mA   -17.9mA    -22.25mA
-700mV    -9.76mA    -9.772mA   -11.84mA
-575mV    -3.248mA   -3.943mA   -3.84mA
-450mV    -304.1uA   -771uA     -250.9uA
1.2V      0A         0A         0A
[POWER_clamp]
|Voltage   I(typ)   I(min)   I(max)
-1.175V   127.9mA    151.5mA    114.4mA
-1.125V   95.11mA    119.3mA    81.3mA
-1.075V   66.05mA    89.76mA    53.26mA
-1.025V   42.55mA    63.81mA    33.28mA
-975mV    26.45mA    42.66mA    22.68mA
-925mV    17.56mA    27.27mA    18.01mA
-875mV    13.18mA    17.5mA     15.4mA
-825mV    10.7mA     11.9mA     13.32mA
-750mV    8.076mA    7.611mA    10.45mA
-500mV    1.821mA    1.817mA    2.516mA
-325mV    164.5uA    258.7uA    189uA
2.4V      -731uA     -642.7uA   -887.3uA
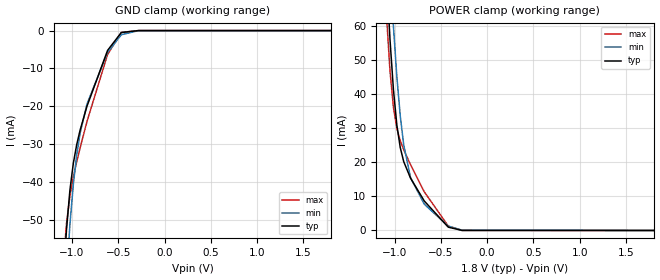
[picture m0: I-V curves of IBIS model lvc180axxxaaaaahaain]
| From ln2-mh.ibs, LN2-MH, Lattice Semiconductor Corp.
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|   Model lvc180axxxaaaaahaain
[Model] lvc180axxxaaaaahaain
Model_type Input
Polarity   Non-Inverting
Enable   Active-High
Vinl =  0.630V
Vinh =  1.170V
C_comp   2.000pF   1.500pF   2.500pF
[Temperature Range]   25.000   0.125k   -40.000
[Voltage Range]   1.800V   1.750V   1.850V
[C Comp Corner]
C_comp   2.000pF   1.500pF   2.500pF
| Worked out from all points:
|   GND clamp passes 1 mA (typ) near -0.50 V on its own axis
|   POWER clamp passes 1 mA (typ) near -0.42 V on its own axis
[GND_clamp]
|Voltage   I(typ)   I(min)   I(max)
-1.8V     -570.7mA   -571.6mA   -572.7mA
-1.097V   -66.78mA   -81.02mA   -62.37mA
-1.06V    -52.56mA   -64.72mA   -50.99mA
-1.023V   -42.13mA   -51.18mA   -43.63mA
-986mV    -34.99mA   -40.57mA   -38.59mA
-949mV    -30.02mA   -32.7mA    -34.54mA
-912mV    -26.2mA    -26.97mA   -30.85mA
-838mV    -19.91mA   -19.32mA   -23.92mA
-616mV    -5.223mA   -5.766mA   -6.295mA
-468mV    -517uA     -1.095mA   -482.2uA
-283mV    -1.785uA   -19.29uA   -453.1nA
1.8V      0A         0A         0A
[POWER_clamp]
|Voltage   I(typ)   I(min)   I(max)
-1.789V   617.6mA    624.8mA    616.1mA
-1.086V   74.43mA    97.5mA     62.76mA
-1.049V   55.98mA    77.5mA     46.8mA
-1.012V   41.32mA    59.89mA    36.12mA
-975mV    30.91mA    45.13mA    29.96mA
-938mV    24.29mA    33.57mA    26.33mA
-901mV    20.21mA    25.16mA    23.7mA
-827mV    15.35mA    15.5mA     19.29mA
-679mV    8.657mA    7.724mA    11.36mA
-420mV    977.9uA    1.256mA    1.313mA
-272mV    22.92uA    106.7uA    14.08uA
1.8V      0A         0A         0A
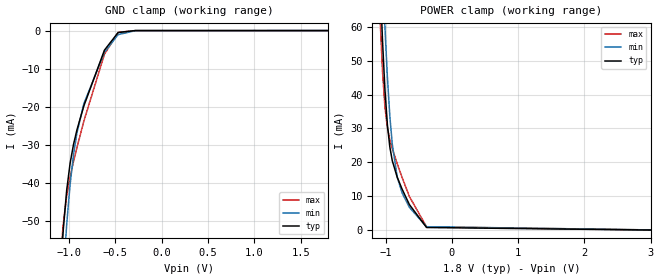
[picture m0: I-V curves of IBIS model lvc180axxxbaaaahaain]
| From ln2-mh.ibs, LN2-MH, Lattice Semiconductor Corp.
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|   Model lvc180axxxbaaaahaain
[Model] lvc180axxxbaaaahaain
Model_type Input
Polarity   Non-Inverting
Enable   Active-High
Vinl =  0.630V
Vinh =  1.170V
C_comp   2.000pF   1.500pF   2.500pF
[Temperature Range]   25.000   0.125k   -40.000
[Voltage Range]   1.800V   1.750V   1.850V
[C Comp Corner]
C_comp   2.000pF   1.500pF   2.500pF
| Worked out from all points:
|   GND clamp passes 1 mA (typ) near -0.50 V on its own axis
|   POWER clamp passes 1 mA (typ) near -0.40 V on its own axis
[GND_clamp]
|Voltage   I(typ)   I(min)   I(max)
-1.8V     -570.6mA   -571.5mA   -572.6mA
-1.097V   -66.69mA   -80.92mA   -62.28mA
-1.06V    -52.47mA   -64.63mA   -50.9mA
-1.023V   -42.04mA   -51.09mA   -43.54mA
-986mV    -34.91mA   -40.48mA   -38.5mA
-949mV    -29.94mA   -32.61mA   -34.45mA
-912mV    -26.11mA   -26.89mA   -30.77mA
-838mV    -19.84mA   -19.25mA   -23.84mA
-616mV    -5.166mA   -5.706mA   -6.235mA
-468mV    -502.7uA   -1.069mA   -469.5uA
-283mV    -1.459uA   -17.21uA   -317.9nA
1.8V      0A         0A         0A
[POWER_clamp]
|Voltage   I(typ)   I(min)   I(max)
-1.789V   617.6mA    624.8mA    616.1mA
-1.086V   74.57mA    97.6mA     62.94mA
-1.049V   56.15mA    77.62mA    47.03mA
-1.012V   41.52mA    60.02mA    36.39mA
-975mV    31.15mA    45.29mA    30.27mA
-938mV    24.56mA    33.75mA    26.65mA
-901mV    20.5mA     25.36mA    24.04mA
-827mV    15.64mA    15.72mA    19.63mA
-753mV    12.1mA     11mA       15.55mA
-642mV    7.512mA    6.704mA    9.896mA
-383mV    772.8uA    998.1uA    969uA
3.6V      -108.1uA   -110.5uA   -109.2uA
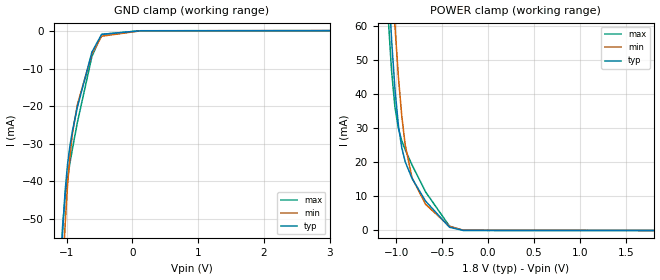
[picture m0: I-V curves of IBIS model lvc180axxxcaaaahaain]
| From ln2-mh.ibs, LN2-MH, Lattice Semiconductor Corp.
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|   Model lvc180axxxcaaaahaain
[Model] lvc180axxxcaaaahaain
Model_type Input
Polarity   Non-Inverting
Enable   Active-High
Vinl =  0.630V
Vinh =  1.170V
C_comp   2.000pF   1.500pF   2.500pF
[Temperature Range]   25.000   0.125k   -40.000
[Voltage Range]   1.800V   1.750V   1.850V
[C Comp Corner]
C_comp   2.000pF   1.500pF   2.500pF
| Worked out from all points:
|   GND clamp passes 1 mA (typ) near -0.47 V on its own axis
|   POWER clamp passes 1 mA (typ) near -0.42 V on its own axis
[GND_clamp]
|Voltage   I(typ)   I(min)   I(max)
-1.8V     -570.8mA   -571.7mA   -572.8mA
-1.097V   -67.02mA   -81.19mA   -62.69mA
-1.06V    -52.84mA   -64.92mA   -51.36mA
-1.023V   -42.45mA   -51.4mA    -44.05mA
-986mV    -35.34mA   -40.82mA   -39.04mA
-949mV    -30.39mA   -32.97mA   -34.99mA
-912mV    -26.58mA   -27.26mA   -31.31mA
-838mV    -20.31mA   -19.63mA   -24.39mA
-616mV    -5.615mA   -6.077mA   -6.765mA
-468mV    -875.4uA   -1.383mA   -917.6uA
124mV     66.78uA    58.31uA    76.02uA
3.6V      104.1uA    122.8uA    104.5uA
[POWER_clamp]
|Voltage   I(typ)   I(min)   I(max)
-1.789V   617.5mA    624.7mA    616mA
-1.086V   74.34mA    97.39mA    62.67mA
-1.049V   55.89mA    77.4mA     46.71mA
-1.012V   41.23mA    59.79mA    36.03mA
-975mV    30.83mA    45.04mA    29.88mA
-938mV    24.21mA    33.48mA    26.24mA
-901mV    20.13mA    25.07mA    23.62mA
-827mV    15.27mA    15.42mA    19.21mA
-679mV    8.587mA    7.649mA    11.28mA
-420mV    942.3uA    1.212mA    1.272mA
-272mV    20.39uA    95.03uA    12.65uA
1.8V      0A         0A         0A
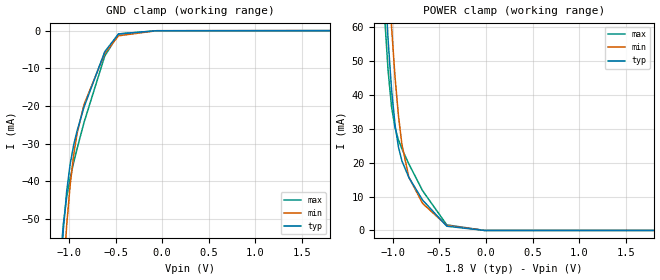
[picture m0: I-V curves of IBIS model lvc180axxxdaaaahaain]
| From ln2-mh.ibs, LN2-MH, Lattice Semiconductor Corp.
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|   Model lvc180axxxdaaaahaain
[Model] lvc180axxxdaaaahaain
Model_type Input
Polarity   Non-Inverting
Enable   Active-High
Vinl =  0.630V
Vinh =  1.170V
C_comp   2.000pF   1.500pF   2.500pF
[Temperature Range]   25.000   0.125k   -40.000
[Voltage Range]   1.800V   1.750V   1.850V
[C Comp Corner]
C_comp   2.000pF   1.500pF   2.500pF
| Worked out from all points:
|   GND clamp passes 1 mA (typ) near -0.47 V on its own axis
|   POWER clamp passes 1 mA (typ) near -0.40 V on its own axis
[GND_clamp]
|Voltage   I(typ)   I(min)   I(max)
-1.8V     -570.8mA   -571.7mA   -572.8mA
-1.097V   -67.02mA   -81.19mA   -62.69mA
-1.06V    -52.84mA   -64.92mA   -51.36mA
-1.023V   -42.45mA   -51.4mA    -44.05mA
-986mV    -35.34mA   -40.82mA   -39.04mA
-949mV    -30.39mA   -32.97mA   -34.99mA
-912mV    -26.58mA   -27.26mA   -31.31mA
-838mV    -20.31mA   -19.63mA   -24.39mA
-616mV    -5.615mA   -6.077mA   -6.765mA
-468mV    -875.4uA   -1.383mA   -917.6uA
-61mV     -41.59uA   -36.04uA   -49.53uA
1.8V      -83.5nA    0A         -36.66uA
[POWER_clamp]
|Voltage   I(typ)   I(min)   I(max)
-1.789V   617.6mA    624.8mA    616.1mA
-1.086V   74.57mA    97.6mA     62.94mA
-1.049V   56.15mA    77.62mA    47.03mA
-1.012V   41.52mA    60.02mA    36.39mA
-975mV    31.15mA    45.29mA    30.27mA
-938mV    24.56mA    33.75mA    26.65mA
-901mV    20.5mA     25.36mA    24.04mA
-827mV    15.64mA    15.72mA    19.63mA
-679mV    8.958mA    7.957mA    11.71mA
-420mV    1.258mA    1.471mA    1.65mA
-13mV     8.76uA     8.311uA    10.26uA
1.8V      0A         0A         35.76uA
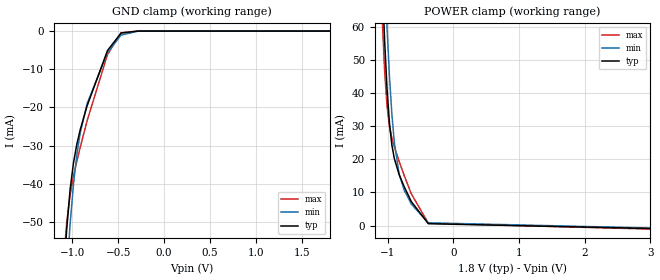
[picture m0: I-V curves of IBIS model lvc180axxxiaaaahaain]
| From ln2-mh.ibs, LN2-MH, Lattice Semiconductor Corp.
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|   Model lvc180axxxiaaaahaain
[Model] lvc180axxxiaaaahaain
Model_type Input
Polarity   Non-Inverting
Enable   Active-High
Vinl =  0.630V
Vinh =  1.170V
C_comp   2.000pF   1.500pF   2.500pF
[Temperature Range]   25.000   0.125k   -40.000
[Voltage Range]   1.800V   1.750V   1.850V
[C Comp Corner]
C_comp   2.000pF   1.500pF   2.500pF
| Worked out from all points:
|   GND clamp passes 1 mA (typ) near -0.50 V on its own axis
|   POWER clamp passes 1 mA (typ) near -0.41 V on its own axis
[GND_clamp]
|Voltage   I(typ)   I(min)   I(max)
-1.8V     -569.7mA   -570.7mA   -571.4mA
-1.097V   -66.1mA    -80.4mA    -61.57mA
-1.06V    -51.94mA   -64.15mA   -50.27mA
-1.023V   -41.57mA   -50.65mA   -42.99mA
-986mV    -34.5mA    -40.09mA   -38.01mA
-949mV    -29.57mA   -32.27mA   -34.01mA
-912mV    -25.79mA   -26.58mA   -30.37mA
-838mV    -19.58mA   -19.01mA   -23.52mA
-616mV    -5.092mA   -5.628mA   -6.132mA
-468mV    -493.6uA   -1.054mA   -457.5uA
-283mV    -1.405uA   -16.93uA   -280.3nA
1.8V      0A         0A         0A
[POWER_clamp]
|Voltage   I(typ)   I(min)   I(max)
-1.789V   617.6mA    624.8mA    616.1mA
-1.086V   74.45mA    97.52mA    62.79mA
-1.049V   56mA       77.52mA    46.83mA
-1.012V   41.34mA    59.91mA    36.16mA
-975mV    30.94mA    45.16mA    30mA
-938mV    24.33mA    33.6mA     26.37mA
-901mV    20.25mA    25.2mA     23.75mA
-827mV    15.39mA    15.54mA    19.34mA
-753mV    11.85mA    10.81mA    15.26mA
-642mV    7.266mA    6.521mA    9.605mA
-383mV    595.8uA    860.9uA    753.9uA
3.6V      -1.113mA   -985.8uA   -1.346mA
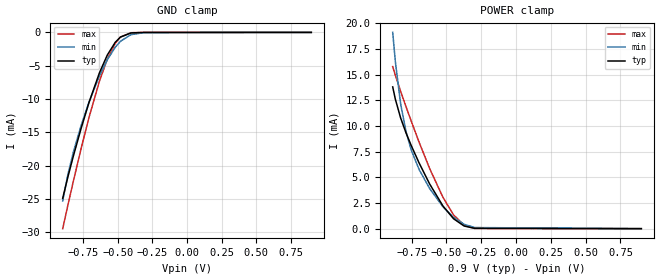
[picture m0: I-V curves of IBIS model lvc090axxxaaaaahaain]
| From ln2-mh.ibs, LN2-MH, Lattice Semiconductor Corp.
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|   Model lvc090axxxaaaaahaain
[Model] lvc090axxxaaaaahaain
Model_type Input
Polarity   Non-Inverting
Enable   Active-High
Vinl =  0.300V
Vinh =  0.600V
C_comp   2.000pF   1.500pF   2.500pF
[Temperature Range]   25.000   0.125k   -40.000
[Voltage Range]   0.900V   0.870V   0.930V
[C Comp Corner]
C_comp   2.000pF   1.500pF   2.500pF
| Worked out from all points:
|   GND clamp passes 1 mA (typ) near -0.50 V on its own axis
|   POWER clamp passes 1 mA (typ) near -0.45 V on its own axis
[GND_clamp]
|Voltage   I(typ)   I(min)   I(max)
-900mV    -24.91mA   -25.31mA   -29.48mA
-862mV    -21.67mA   -21.3mA    -25.91mA
-824mV    -18.66mA   -18.06mA   -22.45mA
-767mV    -14.44mA   -14mA      -17.46mA
-710mV    -10.55mA   -10.5mA    -12.8mA
-634mV    -6.065mA   -6.521mA   -7.324mA
-577mV    -3.399mA   -4.101mA   -4.021mA
-520mV    -1.496mA   -2.239mA   -1.654mA
-482mV    -703uA     -1.339mA   -693.6uA
-406mV    -83.5uA    -337.9uA   -47.56uA
-311mV    -3.589uA   -35.9uA    -940.6nA
900mV     -17.16pA   0A         -11.88pA
[POWER_clamp]
|Voltage   I(typ)   I(min)   I(max)
-886mV    13.81mA    19.12mA    15.79mA
-867mV    12.61mA    16.27mA    14.94mA
-829mV    10.78mA    12.15mA    13.38mA
-791mV    9.351mA    9.485mA    11.9mA
-753mV    8.099mA    7.665mA    10.48mA
-696mV    6.388mA    5.752mA    8.409mA
-620mV    4.338mA    3.895mA    5.839mA
-525mV    2.205mA    2.133mA    3.051mA
-449mV    967uA      1.099mA    1.349mA
-373mV    256.9uA    426.8uA    331.7uA
-297mV    30.15uA    106.2uA    25.19uA
900mV     0A         0A         0A
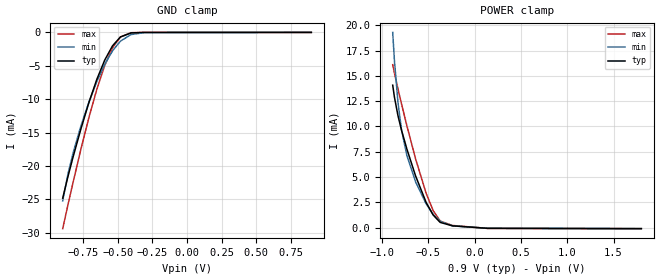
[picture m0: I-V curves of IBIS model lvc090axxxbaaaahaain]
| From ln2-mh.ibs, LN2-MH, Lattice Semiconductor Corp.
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|   Model lvc090axxxbaaaahaain
[Model] lvc090axxxbaaaahaain
Model_type Input
Polarity   Non-Inverting
Enable   Active-High
Vinl =  0.300V
Vinh =  0.600V
C_comp   2.000pF   1.500pF   2.500pF
[Temperature Range]   25.000   0.125k   -40.000
[Voltage Range]   0.900V   0.870V   0.930V
[C Comp Corner]
C_comp   2.000pF   1.500pF   2.500pF
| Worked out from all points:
|   GND clamp passes 1 mA (typ) near -0.50 V on its own axis
|   POWER clamp passes 1 mA (typ) near -0.43 V on its own axis
[GND_clamp]
|Voltage   I(typ)   I(min)   I(max)
-900mV    -24.83mA   -25.24mA   -29.4mA
-862mV    -21.59mA   -21.22mA   -25.83mA
-824mV    -18.59mA   -17.99mA   -22.38mA
-767mV    -14.37mA   -13.93mA   -17.39mA
-710mV    -10.49mA   -10.43mA   -12.73mA
-653mV    -7.038mA   -7.379mA   -8.53mA
-596mV    -4.159mA   -4.797mA   -4.976mA
-539mV    -2mA       -2.751mA   -2.287mA
-482mV    -685.1uA   -1.311mA   -676.6uA
-406mV    -80.56uA   -327.3uA   -45.98uA
-311mV    -3.335uA   -33.95uA   -850.8nA
900mV     0A         0A         0A
[POWER_clamp]
|Voltage   I(typ)   I(min)   I(max)
-886mV    14.08mA    19.3mA     16.11mA
-867mV    12.88mA    16.46mA    15.27mA
-829mV    11.06mA    12.36mA    13.71mA
-791mV    9.635mA    9.695mA    12.24mA
-734mV    7.799mA    7.164mA    10.11mA
-639mV    5.115mA    4.532mA    6.802mA
-525mV    2.491mA    2.349mA    3.394mA
-449mV    1.244mA    1.308mA    1.684mA
-373mV    512.9uA    621.3uA    645.6uA
-240mV    175.8uA    166.1uA    212uA
140mV     -71.31uA   -61.44uA   -81.07uA
1.8V      -102.7uA   -103uA     -104uA
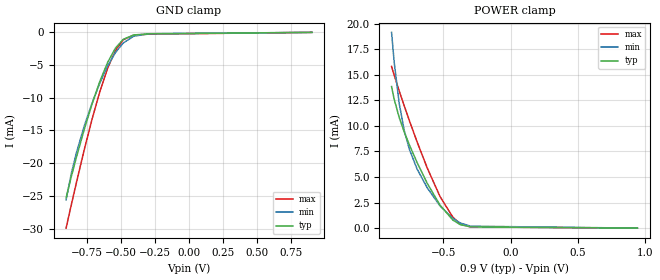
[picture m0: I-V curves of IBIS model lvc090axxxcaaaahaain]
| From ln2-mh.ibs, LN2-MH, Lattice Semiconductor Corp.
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|   Model lvc090axxxcaaaahaain
[Model] lvc090axxxcaaaahaain
Model_type Input
Polarity   Non-Inverting
Enable   Active-High
Vinl =  0.300V
Vinh =  0.600V
C_comp   2.000pF   1.500pF   2.500pF
[Temperature Range]   25.000   0.125k   -40.000
[Voltage Range]   0.900V   0.870V   0.930V
[C Comp Corner]
C_comp   2.000pF   1.500pF   2.500pF
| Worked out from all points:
|   GND clamp passes 1 mA (typ) near -0.48 V on its own axis
|   POWER clamp passes 1 mA (typ) near -0.45 V on its own axis
[GND_clamp]
|Voltage   I(typ)   I(min)   I(max)
-900mV    -25.29mA   -25.6mA    -29.93mA
-862mV    -22.06mA   -21.6mA    -26.37mA
-824mV    -19.05mA   -18.37mA   -22.92mA
-767mV    -14.83mA   -14.31mA   -17.93mA
-710mV    -10.95mA   -10.81mA   -13.27mA
-653mV    -7.49mA    -7.75mA    -9.062mA
-596mV    -4.598mA   -5.157mA   -5.497mA
-539mV    -2.417mA   -3.094mA   -2.785mA
-482mV    -1.066mA   -1.628mA   -1.135mA
-406mV    -400.2uA   -597.8uA   -431uA
-292mV    -223.7uA   -210uA     -267.2uA
900mV     0A         0A         0A
[POWER_clamp]
|Voltage   I(typ)   I(min)   I(max)
-886mV    13.84mA    19.14mA    15.81mA
-867mV    12.63mA    16.29mA    14.97mA
-829mV    10.81mA    12.18mA    13.41mA
-791mV    9.377mA    9.513mA    11.93mA
-753mV    8.127mA    7.695mA    10.5mA
-696mV    6.418mA    5.784mA    8.438mA
-620mV    4.372mA    3.932mA    5.871mA
-525mV    2.248mA    2.177mA    3.091mA
-430mV    797.8uA    952.9uA    1.08mA
-373mV    333uA      494.4uA    407.5uA
-297mV    122.2uA    189.4uA    120.5uA
945mV     0A         0A         0A
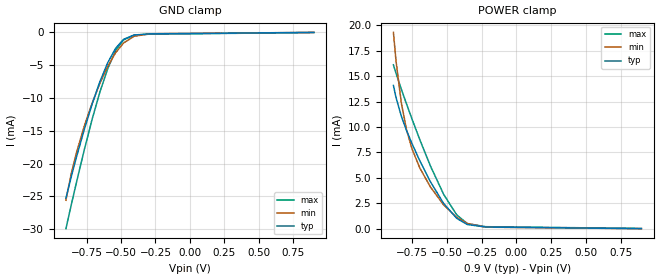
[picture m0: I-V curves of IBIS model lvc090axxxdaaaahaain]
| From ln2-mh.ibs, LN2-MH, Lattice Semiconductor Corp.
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|   Model lvc090axxxdaaaahaain
[Model] lvc090axxxdaaaahaain
Model_type Input
Polarity   Non-Inverting
Enable   Active-High
Vinl =  0.300V
Vinh =  0.600V
C_comp   2.000pF   1.500pF   2.500pF
[Temperature Range]   25.000   0.125k   -40.000
[Voltage Range]   0.900V   0.870V   0.930V
[C Comp Corner]
C_comp   2.000pF   1.500pF   2.500pF
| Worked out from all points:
|   GND clamp passes 1 mA (typ) near -0.48 V on its own axis
|   POWER clamp passes 1 mA (typ) near -0.43 V on its own axis
[GND_clamp]
|Voltage   I(typ)   I(min)   I(max)
-900mV    -25.29mA   -25.6mA    -29.93mA
-862mV    -22.06mA   -21.6mA    -26.37mA
-824mV    -19.05mA   -18.37mA   -22.92mA
-767mV    -14.83mA   -14.31mA   -17.93mA
-710mV    -10.95mA   -10.81mA   -13.27mA
-653mV    -7.49mA    -7.75mA    -9.062mA
-596mV    -4.598mA   -5.157mA   -5.497mA
-539mV    -2.417mA   -3.094mA   -2.785mA
-482mV    -1.066mA   -1.628mA   -1.135mA
-406mV    -400.2uA   -597.8uA   -431uA
-292mV    -223.7uA   -210uA     -267.2uA
900mV     -290.6nA   1.13uA     -22.03uA
[POWER_clamp]
|Voltage   I(typ)   I(min)   I(max)
-886mV    14.08mA    19.3mA     16.11mA
-867mV    12.88mA    16.46mA    15.27mA
-829mV    11.06mA    12.36mA    13.71mA
-791mV    9.635mA    9.695mA    12.24mA
-753mV    8.386mA    7.879mA    10.81mA
-696mV    6.677mA    5.97mA     8.75mA
-620mV    4.627mA    4.114mA    6.183mA
-525mV    2.491mA    2.349mA    3.394mA
-430mV    1.011mA    1.102mA    1.355mA
-354mV    411uA      505.3uA    502.8uA
-221mV    159.2uA    144.5uA    192.7uA
900mV     0A         0A         21.71uA
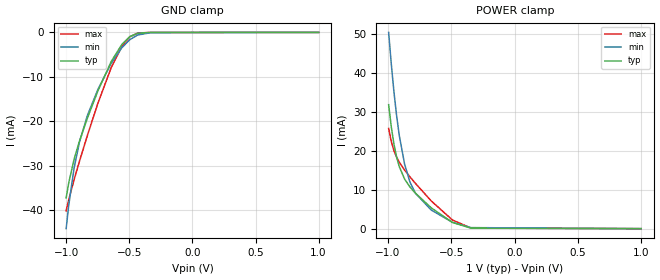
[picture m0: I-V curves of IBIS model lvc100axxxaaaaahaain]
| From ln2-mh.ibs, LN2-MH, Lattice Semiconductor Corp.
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|   Model lvc100axxxaaaaahaain
[Model] lvc100axxxaaaaahaain
Model_type Input
Polarity   Non-Inverting
Enable   Active-High
Vinl =  0.350V
Vinh =  0.650V
C_comp   2.000pF   1.500pF   2.500pF
[Temperature Range]   25.000   0.125k   -40.000
[Voltage Range]   1.000V   0.970V   1.030V
[C Comp Corner]
C_comp   2.000pF   1.500pF   2.500pF
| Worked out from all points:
|   GND clamp passes 1 mA (typ) near -0.50 V on its own axis
|   POWER clamp passes 1 mA (typ) near -0.45 V on its own axis
[GND_clamp]
|Voltage   I(typ)   I(min)   I(max)
-1V       -37.21mA   -44.14mA   -40.12mA
-979mV    -33.76mA   -38.77mA   -37.56mA
-937mV    -28.53mA   -30.51mA   -33.11mA
-895mV    -24.48mA   -24.74mA   -29.03mA
-832mV    -19.3mA    -18.71mA   -23.2mA
-748mV    -13.12mA   -12.79mA   -15.89mA
-643mV    -6.556mA   -6.958mA   -7.929mA
-559mV    -2.714mA   -3.454mA   -3.169mA
-496mV    -952.8uA   -1.641mA   -991.1uA
-433mV    -194.4uA   -584uA     -141.1uA
-328mV    -6.227uA   -54.75uA   -1.801uA
1V        42.04pA    0A         0A
[POWER_clamp]
|Voltage   I(typ)   I(min)   I(max)
-995mV    31.81mA    50.36mA    25.7mA
-974mV    26.08mA    42.19mA    22.34mA
-953mV    21.65mA    35.04mA    20mA
-932mV    18.35mA    28.96mA    18.33mA
-911mV    15.92mA    23.9mA     17.05mA
-869mV    12.73mA    16.55mA    15.04mA
-827mV    10.71mA    11.99mA    13.31mA
-785mV    9.149mA    9.156mA    11.68mA
-659mV    5.357mA    4.783mA    7.128mA
-491mV    1.591mA    1.628mA    2.217mA
-344mV    125.7uA    266.7uA    146.2uA
1V        0A         0A         0A
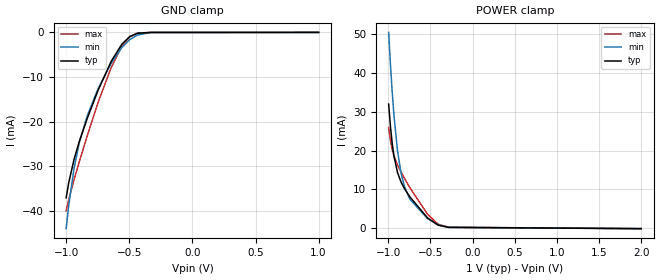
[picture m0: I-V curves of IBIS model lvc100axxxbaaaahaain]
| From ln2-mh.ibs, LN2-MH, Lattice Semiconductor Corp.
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|   Model lvc100axxxbaaaahaain
[Model] lvc100axxxbaaaahaain
Model_type Input
Polarity   Non-Inverting
Enable   Active-High
Vinl =  0.350V
Vinh =  0.650V
C_comp   2.000pF   1.500pF   2.500pF
[Temperature Range]   25.000   0.125k   -40.000
[Voltage Range]   1.000V   0.970V   1.030V
[C Comp Corner]
C_comp   2.000pF   1.500pF   2.500pF
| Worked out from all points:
|   GND clamp passes 1 mA (typ) near -0.50 V on its own axis
|   POWER clamp passes 1 mA (typ) near -0.43 V on its own axis
[GND_clamp]
|Voltage   I(typ)   I(min)   I(max)
-1V       -37.13mA   -44.05mA   -40.03mA
-979mV    -33.67mA   -38.69mA   -37.48mA
-937mV    -28.45mA   -30.43mA   -33.03mA
-895mV    -24.41mA   -24.66mA   -28.95mA
-832mV    -19.23mA   -18.64mA   -23.12mA
-748mV    -13.05mA   -12.72mA   -15.81mA
-643mV    -6.497mA   -6.898mA   -7.866mA
-559mV    -2.671mA   -3.407mA   -3.124mA
-496mV    -930.3uA   -1.608mA   -968.7uA
-433mV    -188.1uA   -567.7uA   -136.8uA
-328mV    -5.866uA   -52.07uA   -1.677uA
1V        0A         0A         0A
[POWER_clamp]
|Voltage   I(typ)   I(min)   I(max)
-995mV    32.01mA    50.49mA    25.97mA
-974mV    26.3mA     42.33mA    22.63mA
-953mV    21.89mA    35.2mA     20.31mA
-932mV    18.6mA     29.12mA    18.65mA
-890mV    14.38mA    19.99mA    16.32mA
-848mV    11.92mA    14.19mA    14.49mA
-806mV    10.18mA    10.62mA    12.83mA
-743mV    8.079mA    7.495mA    10.45mA
-533mV    2.652mA    2.481mA    3.608mA
-407mV    775.9uA    886.3uA    1.02mA
-281mV    222uA      236.7uA    263uA
2V        -103.7uA   -104.4uA   -104.8uA
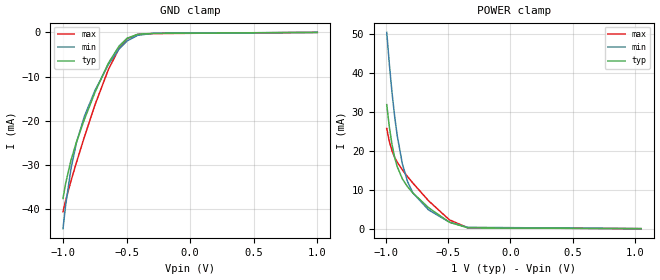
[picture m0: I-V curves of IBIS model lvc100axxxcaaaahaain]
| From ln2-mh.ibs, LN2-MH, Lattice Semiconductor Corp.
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|   Model lvc100axxxcaaaahaain
[Model] lvc100axxxcaaaahaain
Model_type Input
Polarity   Non-Inverting
Enable   Active-High
Vinl =  0.350V
Vinh =  0.650V
C_comp   2.000pF   1.500pF   2.500pF
[Temperature Range]   25.000   0.125k   -40.000
[Voltage Range]   1.000V   0.970V   1.030V
[C Comp Corner]
C_comp   2.000pF   1.500pF   2.500pF
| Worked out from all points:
|   GND clamp passes 1 mA (typ) near -0.48 V on its own axis
|   POWER clamp passes 1 mA (typ) near -0.45 V on its own axis
[GND_clamp]
|Voltage   I(typ)   I(min)   I(max)
-1V       -37.55mA   -44.37mA   -40.55mA
-979mV    -34.11mA   -39.02mA   -38.01mA
-937mV    -28.9mA    -30.79mA   -33.56mA
-895mV    -24.87mA   -25.03mA   -29.49mA
-832mV    -19.69mA   -19.02mA   -23.66mA
-748mV    -13.51mA   -13.1mA    -16.35mA
-643mV    -6.948mA   -7.269mA   -8.398mA
-559mV    -3.098mA   -3.759mA   -3.632mA
-496mV    -1.321mA   -1.935mA   -1.439mA
-412mV    -423.3uA   -647.8uA   -450.9uA
-286mV    -218.8uA   -203.5uA   -261.4uA
1V        0A         0A         0A
[POWER_clamp]
|Voltage   I(typ)   I(min)   I(max)
-995mV    31.83mA    50.38mA    25.72mA
-974mV    26.1mA     42.2mA     22.36mA
-953mV    21.67mA    35.06mA    20.02mA
-932mV    18.37mA    28.98mA    18.35mA
-911mV    15.94mA    23.92mA    17.07mA
-869mV    12.76mA    16.57mA    15.07mA
-827mV    10.73mA    12.02mA    13.34mA
-785mV    9.176mA    9.186mA    11.71mA
-659mV    5.39mA     4.818mA    7.159mA
-491mV    1.64mA     1.677mA    2.263mA
-344mV    211uA      342.5uA    232.8uA
1.05V     0A         0A         0A
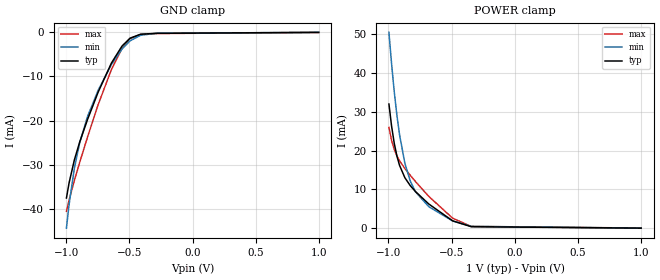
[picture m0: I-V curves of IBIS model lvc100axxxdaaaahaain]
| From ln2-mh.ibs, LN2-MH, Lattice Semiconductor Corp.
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|   Model lvc100axxxdaaaahaain
[Model] lvc100axxxdaaaahaain
Model_type Input
Polarity   Non-Inverting
Enable   Active-High
Vinl =  0.350V
Vinh =  0.650V
C_comp   2.000pF   1.500pF   2.500pF
[Temperature Range]   25.000   0.125k   -40.000
[Voltage Range]   1.000V   0.970V   1.030V
[C Comp Corner]
C_comp   2.000pF   1.500pF   2.500pF
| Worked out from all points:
|   GND clamp passes 1 mA (typ) near -0.48 V on its own axis
|   POWER clamp passes 1 mA (typ) near -0.43 V on its own axis
[GND_clamp]
|Voltage   I(typ)   I(min)   I(max)
-1V       -37.55mA   -44.37mA   -40.55mA
-979mV    -34.11mA   -39.02mA   -38.01mA
-937mV    -28.9mA    -30.79mA   -33.56mA
-895mV    -24.87mA   -25.03mA   -29.49mA
-832mV    -19.69mA   -19.02mA   -23.66mA
-748mV    -13.51mA   -13.1mA    -16.35mA
-643mV    -6.948mA   -7.269mA   -8.398mA
-559mV    -3.098mA   -3.759mA   -3.632mA
-496mV    -1.321mA   -1.935mA   -1.439mA
-412mV    -423.3uA   -647.8uA   -450.9uA
-286mV    -218.8uA   -203.5uA   -261.4uA
1V        -79.89nA   0A         -21.82uA
[POWER_clamp]
|Voltage   I(typ)   I(min)   I(max)
-995mV    32.01mA    50.49mA    25.97mA
-974mV    26.3mA     42.33mA    22.63mA
-953mV    21.89mA    35.2mA     20.31mA
-932mV    18.6mA     29.12mA    18.65mA
-911mV    16.18mA    24.08mA    17.37mA
-869mV    13.01mA    16.74mA    15.37mA
-827mV    10.99mA    12.19mA    13.65mA
-785mV    9.438mA    9.371mA    12.02mA
-680mV    6.228mA    5.537mA    8.194mA
-491mV    1.877mA    1.844mA    2.561mA
-344mV    370.5uA    455uA      446.7uA
1V        0A         0A         21.78uA
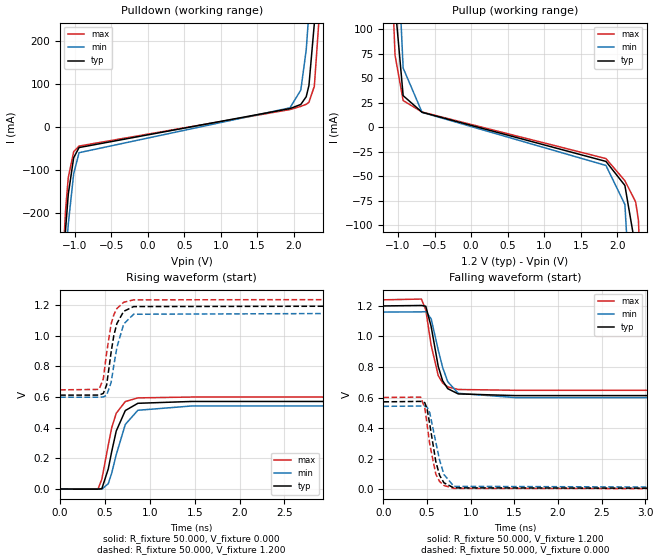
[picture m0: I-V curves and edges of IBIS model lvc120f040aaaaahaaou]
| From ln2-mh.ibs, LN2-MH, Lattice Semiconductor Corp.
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|   Model lvc120f040aaaaahaaou
[Model] lvc120f040aaaaahaaou
Model_type Output
Polarity   Non-Inverting
Enable   Active-High
Vmeas =  0.600V
Cref =  0.0F
Rref =  1.000M
Vref =  0.0V
C_comp   2.000pF   1.500pF   2.500pF
[Temperature Range]   25.000   0.125k   -40.000
[Voltage Range]   1.200V   1.160V   1.240V
[C Comp Corner]
C_comp   2.000pF   1.500pF   2.500pF
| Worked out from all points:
|   slope of the pulldown table from 0 to 0.18 V, typ, clamps not added: 51.9 ohm
|   slope of the pullup table from 0 to 0.18 V, typ, clamps not added: 53.9 ohm
|   rising waveform, R_fixture 50.000, V_fixture 0.000: 20-80 % time 141ps typ, 160ps min, 129ps max; typ from 0 V to 0.572 V
|   rising waveform, R_fixture 50.000, V_fixture 1.200: 20-80 % time 100ps typ, 114ps min, 95.1ps max; typ from 0.613 V to 1.2 V
|   falling waveform, R_fixture 50.000, V_fixture 1.200: 20-80 % time 123ps typ, 153ps min, 113ps max; typ from 1.2 V to 0.613 V
|   falling waveform, R_fixture 50.000, V_fixture 0.000: 20-80 % time 107ps typ, 127ps min, 101ps max; typ from 0.572 V to 0 V
[Pulldown]
|Voltage   I(typ)   I(min)   I(max)
-1.2V     -472.9mA   -546.4mA   -434.3mA
-1.126V   -238.5mA   -315.7mA   -193.7mA
-1.089V   -156.1mA   -225.8mA   -117.3mA
-1.015V   -71.1mA    -108.4mA   -57.23mA
-941mV    -47.45mA   -59.38mA   -43.95mA
1.945V    43.12mA    44.9mA     40.91mA
2.093V    52.76mA    86.27mA    48.33mA
2.167V    70.83mA    179.8mA    53.14mA
2.204V    96.89mA    267.8mA    57.67mA
2.278V    241.2mA    536.5mA    95.05mA
2.352V    542.3mA    903.2mA    275.1mA
2.4V      795.1mA    1.173A     487.3mA
[Pullup]
|Voltage   I(typ)   I(min)   I(max)
-1.2V     776.7mA    926.6mA    694.8mA
-1.115V   353.2mA    504.5mA    265.7mA
-1.078V   218.5mA    356.6mA    143.1mA
-1.041V   125.2mA    238.2mA    73.24mA
-930mV    32.09mA    60.18mA    27.08mA
-671mV    15.15mA    15.05mA    15.39mA
1.845V    -34.91mA   -39.05mA   -32.03mA
2.104V    -59.39mA   -78.78mA   -54.58mA
2.252V    -123.9mA   -267.7mA   -76.35mA
2.289V    -183.8mA   -368.7mA   -94.8mA
2.363V    -393.6mA   -626.7mA   -218.6mA
2.4V      -533.9mA   -776.7mA   -336mA
[Ramp]
| variable   typ   min   max
dV/dt_r   0.343/0.141n   0.326/0.160n   0.360/0.130n
dV/dt_f   0.352/0.123n   0.336/0.154n   0.355/0.113n
R_load = 50.000
[Rising Waveform]
R_fixture = 50.000
V_fixture = 0.000
V_fixture_min = 0.000
V_fixture_max = 0.000
|  time   V(typ)   V(min)   V(max)
0s        2.271uV    10.85uV    1.197uV
422ps     -507uV     -288.7uV   153.1uV
465ps     2.879mV    -725.8uV   64.99mV
536ps     131.1mV    35.02mV    286.1mV
575ps     246.1mV    105mV      401.3mV
625ps     378.8mV    224.9mV    494.6mV
726ps     512.4mV    421.8mV    571.1mV
866ps     559.7mV    514.1mV    595mV
1.466ns   571.7mV    542.3mV    600.5mV
10ns      571.8mV    542.5mV    600.5mV
[Rising Waveform]
R_fixture = 50.000
V_fixture = 1.200
V_fixture_min = 1.160
V_fixture_max = 1.240
|  time   V(typ)   V(min)   V(max)
0s        612.9mV    599.6mV    647.5mV
433ps     613.3mV    599.3mV    650.3mV
481ps     624.1mV    601.1mV    718.5mV
518ps     679.4mV    611.9mV    889.8mV
568ps     893.2mV    695.6mV    1.077V
598ps     1.002V     806.7mV    1.137V
632ps     1.08V      923.7mV    1.178V
708ps     1.16V      1.077V     1.219V
819ps     1.191V     1.141V     1.235V
10ns      1.2V       1.16V      1.24V
[Falling Waveform]
R_fixture = 50.000
V_fixture = 1.200
V_fixture_min = 1.160
V_fixture_max = 1.240
|  time   V(typ)   V(min)   V(max)
0s        1.2V       1.16V      1.24V
435ps     1.203V     1.161V     1.245V
485ps     1.198V     1.163V     1.175V
547ps     1.065V     1.116V     942.2mV
628ps     803.8mV    911.5mV    744.1mV
678ps     710.8mV    798.1mV    695.9mV
737ps     658.2mV    703.8mV    669.8mV
857ps     623.9mV    627.8mV    652.8mV
1.507ns   612.9mV    599.9mV    647.6mV
10ns      612.9mV    599.6mV    647.5mV
[Falling Waveform]
R_fixture = 50.000
V_fixture = 0.000
V_fixture_min = 0.000
V_fixture_max = 0.000
|  time   V(typ)   V(min)   V(max)
0s        571.8mV    542.5mV    600.5mV
426ps     574.8mV    544.4mV    602.9mV
474ps     566.5mV    544.7mV    532.3mV
501ps     524.3mV    537.6mV    422.5mV
531ps     424.8mV    499.9mV    293.6mV
600ps     181.2mV    308.3mV    98.7mV
644ps     90.01mV    189.3mV    50.08mV
694ps     41.52mV    95.42mV    24.02mV
807ps     8.604mV    18.52mV    5.218mV
10ns      2.271uV    10.85uV    1.197uV
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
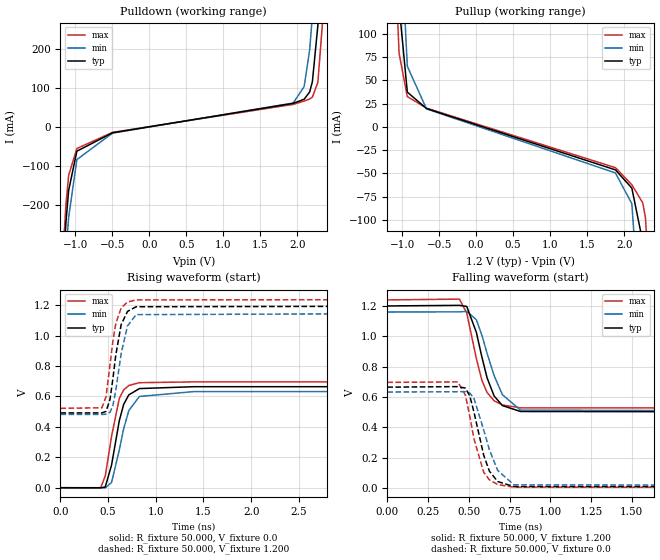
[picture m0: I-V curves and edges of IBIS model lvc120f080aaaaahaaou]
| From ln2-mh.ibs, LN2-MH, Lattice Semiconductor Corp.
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|   Model lvc120f080aaaaahaaou
[Model] lvc120f080aaaaahaaou
Model_type Output
Polarity   Non-Inverting
Enable   Active-High
Vmeas =  0.600V
Cref =  0.0F
Rref =  1.000M
Vref =  0.0V
C_comp   2.000pF   1.500pF   2.500pF
[Temperature Range]   25.000   0.125k   -40.000
[Voltage Range]   1.200V   1.160V   1.240V
[C Comp Corner]
C_comp   2.000pF   1.500pF   2.500pF
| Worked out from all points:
|   slope of the pulldown table from 0 to 0.18 V, typ, clamps not added: 34.6 ohm
|   slope of the pullup table from 0 to 0.18 V, typ, clamps not added: 39.7 ohm
|   rising waveform, R_fixture 50.000, V_fixture 0.0: 20-80 % time 123ps typ, 139ps min, 113ps max; typ from 0 V to 0.664 V
|   rising waveform, R_fixture 50.000, V_fixture 1.200: 20-80 % time 97.3ps typ, 108ps min, 92.3ps max; typ from 0.492 V to 1.2 V
|   falling waveform, R_fixture 50.000, V_fixture 1.200: 20-80 % time 103ps typ, 129ps min, 94.9ps max; typ from 1.2 V to 0.492 V
|   falling waveform, R_fixture 50.000, V_fixture 0.0: 20-80 % time 91.7ps typ, 112ps min, 85.4ps max; typ from 0.664 V to 0 V
[Pulldown]
|Voltage   I(typ)   I(min)   I(max)
-1.2V     -480.2mA   -553.3mA   -441.4mA
-1.126V   -245.7mA   -322.4mA   -200.6mA
-1.089V   -163.2mA   -232.5mA   -124.2mA
-978mV    -62.48mA   -84.09mA   -55.58mA
-497mV    -15.11mA   -15.9mA    -13.96mA
1.945V    60.66mA    61.67mA    58.03mA
2.093V    71.39mA    103.9mA    66.59mA
2.167V    89.91mA    197.7mA    71.94mA
2.204V    116.1mA    285.8mA    76.73mA
2.278V    260.7mA    554.7mA    114.5mA
2.352V    562mA      921.4mA    294.8mA
2.4V      814.8mA    1.192A     507mA
[Pullup]
|Voltage   I(typ)   I(min)   I(max)
-1.2V     782.6mA    932.2mA    701mA
-1.115V   359mA      509.9mA    271.7mA
-1.078V   224.2mA    362mA      149mA
-1.041V   130.8mA    243.6mA    79.06mA
-930mV    37.46mA    65.29mA    32.66mA
-671mV    19.8mA     19.43mA    20.24mA
1.882V    -46.16mA   -49.48mA   -43.81mA
2.104V    -65.78mA   -82.59mA   -62.17mA
2.252V    -123.8mA   -252.8mA   -81.76mA
2.289V    -177.9mA   -343.7mA   -98.37mA
2.363V    -366.8mA   -576mA     -209.8mA
2.4V      -493.2mA   -711mA     -315.6mA
[Ramp]
| variable   typ   min   max
dV/dt_r   0.399/0.123n   0.379/0.139n   0.418/0.113n
dV/dt_f   0.425/0.104n   0.407/0.129n   0.431/94.885p
R_load = 50.000
[Rising Waveform]
R_fixture= 50.000
V_fixture= 0.0
V_fixture_min= 0.0
V_fixture_max= 0.0
|time   V(typ)   V(min)   V(max)
0s        1.132uV    7.8uV      496.3nV
422ps     -647.1uV   -305.9uV   -32.88uV
470ps     4.981mV    -939.9uV   77.39mV
536ps     149.2mV    34.75mV    337.8mV
617ps     440.5mV    247.4mV    587mV
663ps     548.1mV    388.2mV    642.6mV
717ps     610.4mV    507.5mV    672.1mV
828ps     651.9mV    600mV      690.6mV
1.397ns   664.2mV    631.9mV    695.8mV
10ns      664.3mV    632.1mV    695.8mV
[Rising Waveform]
R_fixture= 50.000
V_fixture= 1.200
V_fixture_min= 1.160
V_fixture_max= 1.240
|time   V(typ)   V(min)   V(max)
0s        491.7mV    482.1mV    522.1mV
435ps     491.9mV    481.8mV    525.7mV
478ps     501.9mV    483.3mV    598.4mV
520ps     581.1mV    496.1mV    810.6mV
551ps     722mV      542.7mV    968mV
580ps     871.5mV    639.8mV    1.078V
637ps     1.073V     883mV      1.182V
703ps     1.159V     1.064V     1.221V
794ps     1.19V      1.138V     1.235V
10ns      1.2V       1.16V      1.24V
[Falling Waveform]
R_fixture= 50.000
V_fixture= 1.200
V_fixture_min= 1.160
V_fixture_max= 1.240
|time   V(typ)   V(min)   V(max)
0s        1.2V       1.16V      1.24V
442ps     1.204V     1.161V     1.245V
487ps     1.197V     1.164V     1.154V
546ps     1.026V     1.109V     853.5mV
580ps     863.1mV    1.007V     708.6mV
612ps     725.1mV    887.1mV    628.7mV
655ps     605.9mV    740mV      574.6mV
706ps     542.8mV    614.1mV    546.4mV
817ps     503.7mV    512.9mV    527.9mV
10ns      491.7mV    482.1mV    522.1mV
[Falling Waveform]
R_fixture= 50.000
V_fixture= 0.0
V_fixture_min= 0.0
V_fixture_max= 0.0
|time   V(typ)   V(min)   V(max)
0s        664.3mV    632.1mV    695.8mV
432ps     667.9mV    634.2mV    699mV
479ps     658mV      634.6mV    612mV
506ps     605.8mV    625.4mV    469.6mV
532ps     497.3mV    588.3mV    320.7mV
591ps     215.2mV    382.1mV    102.8mV
626ps     110.3mV    251.4mV    52.9mV
677ps     41.72mV    114.7mV    21.65mV
777ps     8.166mV    20.12mV    4.696mV
10ns      1.146uV    7.813uV    517.8nV
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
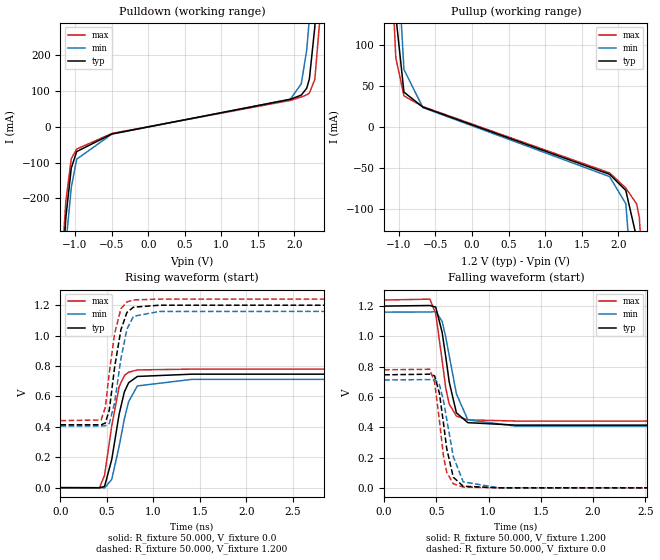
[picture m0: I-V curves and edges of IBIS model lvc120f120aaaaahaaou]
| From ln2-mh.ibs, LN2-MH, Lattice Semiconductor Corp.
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|   Model lvc120f120aaaaahaaou
[Model] lvc120f120aaaaahaaou
Model_type Output
Polarity   Non-Inverting
Enable   Active-High
Vmeas =  0.600V
Cref =  0.0F
Rref =  1.000M
Vref =  0.0V
C_comp   2.000pF   1.500pF   2.500pF
[Temperature Range]   25.000   0.125k   -40.000
[Voltage Range]   1.200V   1.160V   1.240V
[C Comp Corner]
C_comp   2.000pF   1.500pF   2.500pF
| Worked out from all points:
|   slope of the pulldown table from 0 to 0.18 V, typ, clamps not added: 26.2 ohm
|   slope of the pullup table from 0 to 0.18 V, typ, clamps not added: 30.1 ohm
|   rising waveform, R_fixture 50.000, V_fixture 0.0: 20-80 % time 131ps typ, 146ps min, 118ps max; typ from 0 V to 0.746 V
|   rising waveform, R_fixture 50.000, V_fixture 1.200: 20-80 % time 113ps typ, 119ps min, 105ps max; typ from 0.413 V to 1.2 V
|   falling waveform, R_fixture 50.000, V_fixture 1.200: 20-80 % time 105ps typ, 130ps min, 94.8ps max; typ from 1.2 V to 0.413 V
|   falling waveform, R_fixture 50.000, V_fixture 0.0: 20-80 % time 91.8ps typ, 116ps min, 81.8ps max; typ from 0.746 V to 0 V
[Pulldown]
|Voltage   I(typ)   I(min)   I(max)
-1.2V     -487.2mA   -559.9mA   -448.1mA
-1.126V   -252.5mA   -328.8mA   -207.3mA
-1.052V   -115.2mA   -169.5mA   -88.73mA
-978mV    -68.96mA   -90.18mA   -61.85mA
-497mV    -19.61mA   -20.14mA   -18.29mA
1.945V    77.37mA    77.65mA    74.28mA
2.093V    89.11mA    120.7mA    83.89mA
2.167V    108.1mA    214.7mA    89.76mA
2.204V    134.4mA    303mA      94.78mA
2.278V    279.2mA    571.9mA    132.9mA
2.352V    580.6mA    938.7mA    313.4mA
2.4V      833.5mA    1.209A     525.7mA
[Pullup]
|Voltage   I(typ)   I(min)   I(max)
-1.2V     788.2mA    937.5mA    706.8mA
-1.115V   364.5mA    515.2mA    277.4mA
-1.078V   229.6mA    367.2mA    154.6mA
-1.041V   136.2mA    248.8mA    84.62mA
-930mV    42.62mA    70.24mA    37.98mA
-671mV    24.27mA    23.67mA    24.88mA
1.882V    -57.97mA   -60.75mA   -56.19mA
2.104V    -77.72mA   -93.94mA   -74.75mA
2.252V    -135.8mA   -264.1mA   -94.34mA
2.289V    -189.7mA   -355mA     -110.9mA
2.363V    -378.7mA   -587.1mA   -222.4mA
2.4V      -505mA     -722mA     -328.1mA
[Ramp]
| variable   typ   min   max
dV/dt_r   0.448/0.131n   0.428/0.146n   0.468/0.118n
dV/dt_f   0.472/0.105n   0.452/0.130n   0.480/94.847p
R_load = 50.000
[Rising Waveform]
R_fixture= 50.000
V_fixture= 0.0
V_fixture_min= 0.0
V_fixture_max= 0.0
|time   V(typ)   V(min)   V(max)
0s        922.6nV    6.444uV    405.2nV
420ps     -752.4uV   -299.3uV   -555.1uV
475ps     8.098mV    -1.353mV   81.63mV
552ps     184.6mV    54mV       406.1mV
632ps     484.1mV    272.9mV    665mV
688ps     629.8mV    452.2mV    737mV
734ps     690.1mV    565.9mV    759.2mV
828ps     731.4mV    669.1mV    774.3mV
1.417ns   746.4mV    712.3mV    779.6mV
10ns      746.4mV    712.5mV    779.6mV
[Rising Waveform]
R_fixture= 50.000
V_fixture= 1.200
V_fixture_min= 1.160
V_fixture_max= 1.240
|time   V(typ)   V(min)   V(max)
0s        413.5mV    406.2mV    440.8mV
438ps     413.4mV    405.8mV    445.3mV
483ps     424.8mV    407.1mV    527.8mV
526ps     510.9mV    422.3mV    758.2mV
583ps     792.1mV    559.3mV    1.013V
651ps     1.039V     849mV      1.177V
716ps     1.153V     1.043V     1.222V
786ps     1.187V     1.127V     1.235V
1.066ns   1.2V       1.159V     1.24V
10ns      1.2V       1.16V      1.24V
[Falling Waveform]
R_fixture= 50.000
V_fixture= 1.200
V_fixture_min= 1.160
V_fixture_max= 1.240
|time   V(typ)   V(min)   V(max)
0s        1.2V       1.16V      1.24V
438ps     1.204V     1.161V     1.246V
494ps     1.193V     1.164V     1.149V
555ps     1.027V     1.099V     842.3mV
590ps     864mV      995.1mV    657.6mV
623ps     698.8mV    872.3mV    553.5mV
692ps     495.2mV    620.7mV    474.2mV
801ps     430.5mV    449mV      448.8mV
1.261ns   414.2mV    407.8mV    441.1mV
10ns      413.5mV    406.2mV    440.8mV
[Falling Waveform]
R_fixture= 50.000
V_fixture= 0.0
V_fixture_min= 0.0
V_fixture_max= 0.0
|time   V(typ)   V(min)   V(max)
0s        746.4mV    712.5mV    779.6mV
436ps     750.4mV    714.8mV    783mV
483ps     739.5mV    715.2mV    697.5mV
529ps     625mV      682mV      443.8mV
568ps     427.1mV    576.9mV    209.3mV
599ps     259.8mV    453.2mV    103.1mV
662ps     70.31mV    206.2mV    26.75mV
757ps     10.64mV    39.38mV    5.253mV
1.096ns   371.6uV    636.3uV    210.8uV
10ns      934.3nV    6.449uV    424.5nV
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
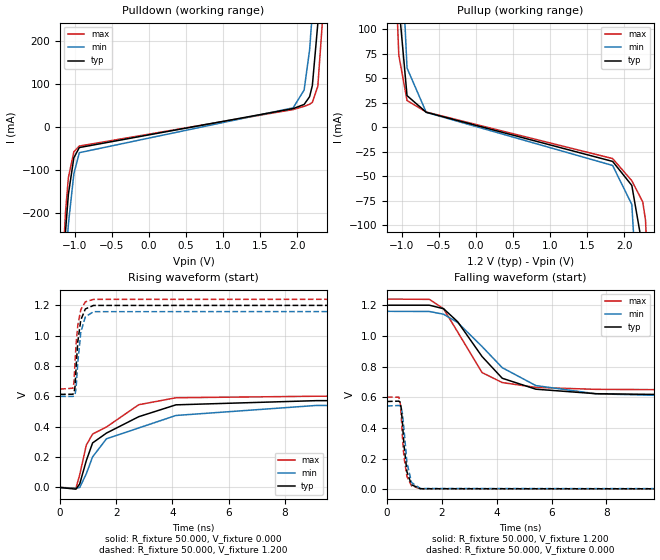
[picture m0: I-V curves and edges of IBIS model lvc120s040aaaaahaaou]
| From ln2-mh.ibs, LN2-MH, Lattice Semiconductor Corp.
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|   Model lvc120s040aaaaahaaou
[Model] lvc120s040aaaaahaaou
Model_type Output
Polarity   Non-Inverting
Enable   Active-High
Vmeas =  0.600V
Cref =  0.0F
Rref =  1.000M
Vref =  0.0V
C_comp   2.000pF   1.500pF   2.500pF
[Temperature Range]   25.000   0.125k   -40.000
[Voltage Range]   1.200V   1.160V   1.240V
[C Comp Corner]
C_comp   2.000pF   1.500pF   2.500pF
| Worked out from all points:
|   slope of the pulldown table from 0 to 0.18 V, typ, clamps not added: 51.9 ohm
|   slope of the pullup table from 0 to 0.18 V, typ, clamps not added: 53.9 ohm
|   rising waveform, R_fixture 50.000, V_fixture 0.000: 20-80 % time 1.87ns typ, 2.45ns min, 1.49ns max; typ from 0 V to 0.572 V
|   rising waveform, R_fixture 50.000, V_fixture 1.200: 20-80 % time 162ps typ, 171ps min, 159ps max; typ from 0.613 V to 1.2 V
|   falling waveform, R_fixture 50.000, V_fixture 1.200: 20-80 % time 1.53ns typ, 2.04ns min, 1.16ns max; typ from 1.2 V to 0.613 V
|   falling waveform, R_fixture 50.000, V_fixture 0.000: 20-80 % time 171ps typ, 185ps min, 164ps max; typ from 0.572 V to 0 V
[Pulldown]
|Voltage   I(typ)   I(min)   I(max)
-1.2V     -472.9mA   -546.4mA   -434.3mA
-1.126V   -238.5mA   -315.7mA   -193.7mA
-1.089V   -156.1mA   -225.8mA   -117.3mA
-1.015V   -71.1mA    -108.4mA   -57.23mA
-941mV    -47.45mA   -59.38mA   -43.95mA
1.945V    43.12mA    44.9mA     40.91mA
2.093V    52.76mA    86.27mA    48.33mA
2.167V    70.83mA    179.8mA    53.14mA
2.204V    96.89mA    267.8mA    57.67mA
2.278V    241.2mA    536.5mA    95.05mA
2.352V    542.3mA    903.2mA    275.1mA
2.4V      795.1mA    1.173A     487.3mA
[Pullup]
|Voltage   I(typ)   I(min)   I(max)
-1.2V     776.7mA    926.6mA    694.8mA
-1.115V   353.2mA    504.5mA    265.7mA
-1.078V   218.5mA    356.6mA    143.1mA
-1.041V   125.2mA    238.2mA    73.24mA
-930mV    32.09mA    60.18mA    27.08mA
-671mV    15.15mA    15.05mA    15.39mA
1.845V    -34.91mA   -39.05mA   -32.03mA
2.104V    -59.39mA   -78.78mA   -54.58mA
2.252V    -123.9mA   -267.7mA   -76.35mA
2.289V    -183.8mA   -368.7mA   -94.8mA
2.363V    -393.6mA   -626.7mA   -218.6mA
2.4V      -533.9mA   -776.7mA   -336mA
[Ramp]
| variable   typ   min   max
dV/dt_r   0.343/1.876n   0.325/2.458n   0.360/1.495n
dV/dt_f   0.352/1.535n   0.336/2.048n   0.355/1.163n
R_load = 50.000
[Rising Waveform]
R_fixture = 50.000
V_fixture = 0.000
V_fixture_min = 0.000
V_fixture_max = 0.000
|  time   V(typ)   V(min)   V(max)
0s        2.271uV    10.85uV    1.197uV
564ps     -11.09mV   -6.006mV   -3.848mV
697ps     23.42mV    -408.9uV   83.7mV
931ps     176.2mV    89.96mV    278.5mV
1.156ns   293.3mV    201.4mV    351.5mV
1.651ns   358mV      320.6mV    398.3mV
2.801ns   465.9mV    391.8mV    544.7mV
4.126ns   543.9mV    473.9mV    590.5mV
9.123ns   571.4mV    539.8mV    600.5mV
50ns      571.8mV    542.5mV    600.5mV
[Rising Waveform]
R_fixture = 50.000
V_fixture = 1.200
V_fixture_min = 1.160
V_fixture_max = 1.240
|  time   V(typ)   V(min)   V(max)
0s        612.9mV    599.6mV    647.5mV
456ps     613.8mV    599.4mV    653.3mV
492ps     621.4mV    601.9mV    690.2mV
531ps     664.1mV    612.5mV    830.2mV
568ps     790.4mV    655.4mV    945.1mV
629ps     959.3mV    822.6mV    1.067V
735ps     1.102V     1.021V     1.17V
898ps     1.175V     1.123V     1.222V
1.188ns   1.198V     1.157V     1.238V
50ns      1.2V       1.16V      1.24V
[Falling Waveform]
R_fixture = 50.000
V_fixture = 1.200
V_fixture_min = 1.160
V_fixture_max = 1.240
|  time   V(typ)   V(min)   V(max)
0s        1.2V       1.16V      1.24V
1.545ns   1.2V       1.159V     1.238V
2.062ns   1.177V     1.141V     1.177V
2.576ns   1.092V     1.087V     1.025V
3.465ns   865.4mV    930.6mV    760.6mV
4.202ns   723.5mV    792.4mV    695.4mV
5.427ns   652.1mV    675.7mV    663.9mV
7.625ns   622.6mV    622mV      651mV
11.59ns   614.1mV    603.8mV    647.8mV
50ns      612.9mV    599.6mV    647.5mV
[Falling Waveform]
R_fixture = 50.000
V_fixture = 0.000
V_fixture_min = 0.000
V_fixture_max = 0.000
|  time   V(typ)   V(min)   V(max)
0s        571.8mV    542.5mV    600.5mV
431ps     574.3mV    545.7mV    600mV
474ps     567.3mV    544.2mV    572.2mV
512ps     535.2mV    536.6mV    496.5mV
564ps     430.5mV    489.7mV    337.4mV
616ps     291.6mV    394.8mV    212.4mV
726ps     112.9mV    174.4mV    83.04mV
893ps     28.81mV    43.81mV    21.51mV
1.216ns   3.069mV    4.166mV    2.571mV
50ns      2.271uV    10.85uV    1.197uV
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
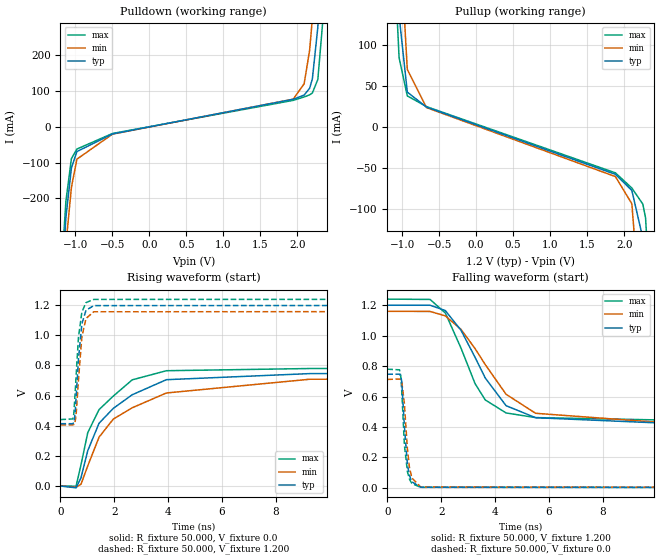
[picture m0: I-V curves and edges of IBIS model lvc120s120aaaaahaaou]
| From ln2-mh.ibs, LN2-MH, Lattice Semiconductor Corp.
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|   Model lvc120s120aaaaahaaou
[Model] lvc120s120aaaaahaaou
Model_type Output
Polarity   Non-Inverting
Enable   Active-High
Vmeas =  0.600V
Cref =  0.0F
Rref =  1.000M
Vref =  0.0V
C_comp   2.000pF   1.500pF   2.500pF
[Temperature Range]   25.000   0.125k   -40.000
[Voltage Range]   1.200V   1.160V   1.240V
[C Comp Corner]
C_comp   2.000pF   1.500pF   2.500pF
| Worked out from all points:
|   slope of the pulldown table from 0 to 0.18 V, typ, clamps not added: 26.2 ohm
|   slope of the pullup table from 0 to 0.18 V, typ, clamps not added: 30.1 ohm
|   rising waveform, R_fixture 50.000, V_fixture 0.0: 20-80 % time 1.7ns typ, 2.24ns min, 1.34ns max; typ from 0 V to 0.746 V
|   rising waveform, R_fixture 50.000, V_fixture 1.200: 20-80 % time 190ps typ, 192ps min, 183ps max; typ from 0.414 V to 1.2 V
|   falling waveform, R_fixture 50.000, V_fixture 1.200: 20-80 % time 1.51ns typ, 1.88ns min, 1.18ns max; typ from 1.2 V to 0.413 V
|   falling waveform, R_fixture 50.000, V_fixture 0.0: 20-80 % time 170ps typ, 188ps min, 163ps max; typ from 0.746 V to 0 V
[Pulldown]
|Voltage   I(typ)   I(min)   I(max)
-1.2V     -487.2mA   -559.9mA   -448.1mA
-1.126V   -252.5mA   -328.8mA   -207.3mA
-1.052V   -115.2mA   -169.5mA   -88.73mA
-978mV    -68.96mA   -90.18mA   -61.85mA
-497mV    -19.61mA   -20.14mA   -18.29mA
1.945V    77.37mA    77.65mA    74.28mA
2.093V    89.11mA    120.7mA    83.89mA
2.167V    108.1mA    214.7mA    89.76mA
2.204V    134.4mA    303mA      94.78mA
2.278V    279.2mA    571.9mA    132.9mA
2.352V    580.6mA    938.7mA    313.4mA
2.4V      833.5mA    1.209A     525.7mA
[Pullup]
|Voltage   I(typ)   I(min)   I(max)
-1.2V     788.2mA    937.5mA    706.8mA
-1.115V   364.5mA    515.2mA    277.4mA
-1.078V   229.6mA    367.2mA    154.6mA
-1.041V   136.2mA    248.8mA    84.62mA
-930mV    42.62mA    70.24mA    37.98mA
-671mV    24.27mA    23.67mA    24.88mA
1.882V    -57.97mA   -60.75mA   -56.19mA
2.104V    -77.72mA   -93.93mA   -74.75mA
2.252V    -135.8mA   -264mA     -94.34mA
2.289V    -189.7mA   -355mA     -110.9mA
2.363V    -378.7mA   -587.1mA   -222.4mA
2.4V      -505mA     -722mA     -328.1mA
[Ramp]
| variable   typ   min   max
dV/dt_r   0.448/1.703n   0.428/2.238n   0.468/1.337n
dV/dt_f   0.472/1.511n   0.452/1.892n   0.480/1.178n
R_load = 50.000
[Rising Waveform]
R_fixture= 50.000
V_fixture= 0.0
V_fixture_min= 0.0
V_fixture_max= 0.0
|time   V(typ)   V(min)   V(max)
0s        922.6nV    6.444uV    405.2nV
580ps     -12.27mV   -8.717mV   -1.119mV
764ps     55.27mV    11.94mV    141.3mV
1.015ns   234.7mV    134.1mV    354.7mV
1.434ns   416.5mV    324.1mV    507.1mV
1.964ns   515.4mV    444.2mV    596.8mV
2.666ns   605.6mV    519.1mV    704.5mV
3.936ns   705.5mV    617.3mV    765mV
9.265ns   745.9mV    708.5mV    779.6mV
50ns      746.4mV    712.5mV    779.6mV
[Rising Waveform]
R_fixture= 50.000
V_fixture= 1.200
V_fixture_min= 1.160
V_fixture_max= 1.240
|time   V(typ)   V(min)   V(max)
0s        413.5mV    406.2mV    440.8mV
459ps     413.4mV    405.6mV    445mV
496ps     420.8mV    407.8mV    478.6mV
542ps     475.3mV    421.5mV    608.1mV
586ps     598.5mV    483.6mV    744.6mV
670ps     844.3mV    706.1mV    989.9mV
796ps     1.077V     992.2mV    1.154V
950ps     1.166V     1.112V     1.217V
1.237ns   1.197V     1.156V     1.238V
50ns      1.2V       1.16V      1.24V
[Falling Waveform]
R_fixture= 50.000
V_fixture= 1.200
V_fixture_min= 1.160
V_fixture_max= 1.240
|time   V(typ)   V(min)   V(max)
0s        1.2V       1.16V      1.24V
1.586ns   1.2V       1.159V     1.238V
2.153ns   1.165V     1.13V      1.149V
2.736ns   1.035V     1.041V     917.5mV
3.257ns   857.3mV    914.9mV    684.4mV
3.634ns   721.9mV    810mV      577.7mV
4.407ns   540mV      614.8mV    492.2mV
5.503ns   460.9mV    489.9mV    461.7mV
11.51ns   415.6mV    411.7mV    441.4mV
50ns      413.5mV    406.2mV    440.8mV
[Falling Waveform]
R_fixture= 50.000
V_fixture= 0.0
V_fixture_min= 0.0
V_fixture_max= 0.0
|time   V(typ)   V(min)   V(max)
0s        746.4mV    712.5mV    779.6mV
452ps     747mV      715.1mV    775.6mV
496ps     736mV      711.6mV    738.9mV
533ps     700mV      700.4mV    645.7mV
633ps     406.7mV    553.9mV    282.8mV
745ps     154mV      255.8mV    107.8mV
817ps     84.01mV    139mV      59.36mV
907ps     40.32mV    65.82mV    28.9mV
1.236ns   4.197mV    5.796mV    3.535mV
50ns      927.8nV    6.454uV    412.8nV
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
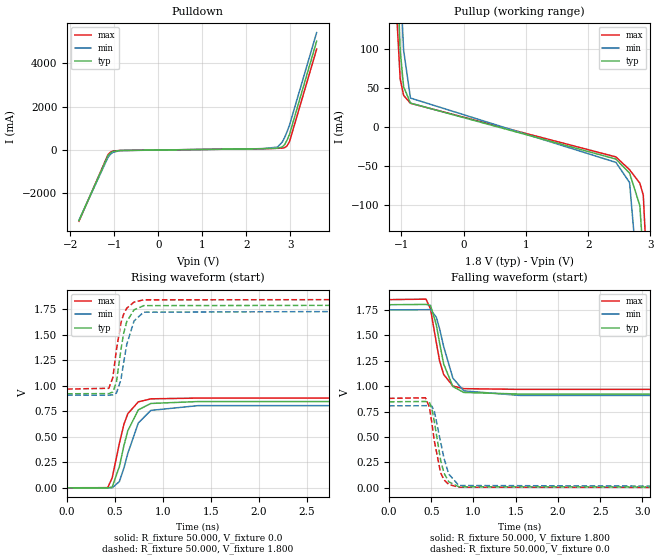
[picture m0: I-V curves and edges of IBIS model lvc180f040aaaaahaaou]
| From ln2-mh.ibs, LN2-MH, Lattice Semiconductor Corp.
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|   Model lvc180f040aaaaahaaou
[Model] lvc180f040aaaaahaaou
Model_type Output
Polarity   Non-Inverting
Enable   Active-High
Vmeas =  0.900V
Cref =  0.0F
Rref =  1.000M
Vref =  0.0V
C_comp   2.000pF   1.500pF   2.500pF
[Temperature Range]   25.000   0.125k   -40.000
[Voltage Range]   1.800V   1.750V   1.850V
[C Comp Corner]
C_comp   2.000pF   1.500pF   2.500pF
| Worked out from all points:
|   slope of the pulldown table from 0 to 0.27 V, typ, clamps not added: 52 ohm
|   slope of the pullup table from 0 to 0.27 V, typ, clamps not added: 54.3 ohm
|   rising waveform, R_fixture 50.000, V_fixture 0.0: 20-80 % time 145ps typ, 166ps min, 132ps max; typ from 0 V to 0.846 V
|   rising waveform, R_fixture 50.000, V_fixture 1.800: 20-80 % time 95.2ps typ, 108ps min, 90.7ps max; typ from 0.922 V to 1.8 V
|   falling waveform, R_fixture 50.000, V_fixture 1.800: 20-80 % time 134ps typ, 164ps min, 121ps max; typ from 1.8 V to 0.922 V
|   falling waveform, R_fixture 50.000, V_fixture 0.0: 20-80 % time 110ps typ, 128ps min, 105ps max; typ from 0.846 V to 0 V
[Pulldown]
|Voltage   I(typ)   I(min)   I(max)
-1.8V     -3.291A    -3.274A    -3.322A
-1.14V    -276.9mA   -354.6mA   -231.7mA
-1.085V   -149.1mA   -217.6mA   -111.5mA
-1.03V    -81.34mA   -125.8mA   -63.07mA
-865mV    -37.99mA   -41.38mA   -36.12mA
2.38V     46.17mA    46.48mA    43.45mA
2.71V     67.87mA    120.2mA    62.04mA
2.82V     127.2mA    357.1mA    72.79mA
2.875V    242.3mA    575.2mA    95.86mA
2.93V     447.5mA    845mA      183.2mA
2.985V    723mA      1.153A     382mA
3.6V      5.031A     5.432A     4.663A
[Pullup]
|Voltage   I(typ)   I(min)   I(max)
-1.8V     5.013A     5.045A     5.026A
-1.13V    424.1mA    576.9mA    336mA
-1.075V   216.1mA    351.6mA    143.6mA
-1.02V    98.11mA    191.4mA    61.81mA
-965mV    51.8mA     98.91mA    40.64mA
-855mV    30.69mA    37.2mA     30.43mA
2.445V    -41.43mA   -45.64mA   -38.61mA
2.665V    -59.52mA   -71.66mA   -55.11mA
2.83V     -101.4mA   -225.3mA   -72.51mA
2.885V    -168mA     -357.6mA   -87.76mA
2.995V    -471.8mA   -727.1mA   -265.7mA
3.6V      -3.302A    -3.533A    -3.08A
[Ramp]
| variable   typ   min   max
dV/dt_r   0.507/0.145n   0.484/0.166n   0.528/0.132n
dV/dt_f   0.527/0.134n   0.505/0.165n   0.529/0.122n
R_load = 50.000
[Rising Waveform]
R_fixture= 50.000
V_fixture= 0.0
V_fixture_min= 0.0
V_fixture_max= 0.0
|time   V(typ)   V(min)   V(max)
0s        2.741uV    16.36uV    1.179uV
424ps     -507.9uV   -299.1uV   879.4uV
471ps     8.016mV    -803.3uV   97.25mV
546ps     207.8mV    61.07mV    434.6mV
594ps     415.1mV    194.6mV    624.3mV
634ps     559.3mV    336.8mV    726.3mV
744ps     764.5mV    635.6mV    842.6mV
875ps     827.1mV    758.9mV    872.1mV
1.365ns   845.5mV    805.4mV    879.7mV
10ns      845.7mV    806.3mV    879.8mV
[Rising Waveform]
R_fixture= 50.000
V_fixture= 1.800
V_fixture_min= 1.750
V_fixture_max= 1.850
|time   V(typ)   V(min)   V(max)
0s        921.8mV    908.1mV    968mV
436ps     923.2mV    908mV      975.5mV
478ps     939.1mV    911.6mV    1.081V
515ps     1.035V     928.3mV    1.351V
562ps     1.352V     1.059V     1.617V
591ps     1.516V     1.229V     1.703V
623ps     1.628V     1.405V     1.761V
699ps     1.745V     1.636V     1.821V
800ps     1.786V     1.722V     1.843V
10ns      1.8V       1.75V      1.85V
[Falling Waveform]
R_fixture= 50.000
V_fixture= 1.800
V_fixture_min= 1.750
V_fixture_max= 1.850
|time   V(typ)   V(min)   V(max)
0s        1.8V       1.75V      1.85V
438ps     1.803V     1.751V     1.855V
491ps     1.794V     1.753V     1.76V
560ps     1.603V     1.677V     1.428V
599ps     1.425V     1.563V     1.249V
647ps     1.218V     1.389V     1.114V
756ps     995.6mV    1.079V     1.001V
886ps     937.8mV    953.2mV    975mV
1.547ns   921.9mV    908.5mV    968mV
10ns      921.8mV    908.1mV    968mV
[Falling Waveform]
R_fixture= 50.000
V_fixture= 0.0
V_fixture_min= 0.0
V_fixture_max= 0.0
|time   V(typ)   V(min)   V(max)
0s        845.7mV    806.3mV    879.8mV
432ps     849mV      807.3mV    885.1mV
478ps     842.9mV    810.5mV    794.4mV
507ps     782.2mV    802.5mV    638.9mV
537ps     647.7mV    752.2mV    459.7mV
611ps     272.8mV    450.5mV    148.1mV
651ps     145.6mV    290.8mV    78.48mV
707ps     59.78mV    135.8mV    33.63mV
827ps     10.81mV    23.14mV    6.525mV
10ns      2.86uV     16.46uV    1.237uV
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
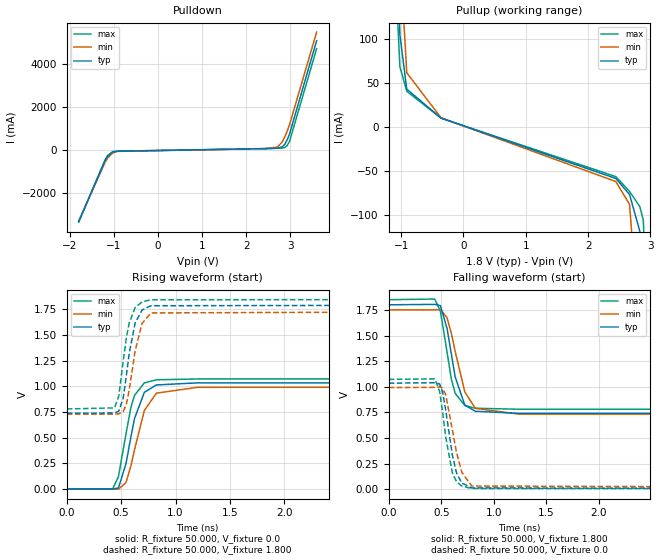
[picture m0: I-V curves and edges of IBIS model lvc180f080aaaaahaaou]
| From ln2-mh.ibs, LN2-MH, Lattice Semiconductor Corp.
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|   Model lvc180f080aaaaahaaou
[Model] lvc180f080aaaaahaaou
Model_type Output
Polarity   Non-Inverting
Enable   Active-High
Vmeas =  0.900V
Cref =  0.0F
Rref =  1.000M
Vref =  0.0V
C_comp   2.000pF   1.500pF   2.500pF
[Temperature Range]   25.000   0.125k   -40.000
[Voltage Range]   1.800V   1.750V   1.850V
[C Comp Corner]
C_comp   2.000pF   1.500pF   2.500pF
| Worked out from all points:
|   slope of the pulldown table from 0 to 0.27 V, typ, clamps not added: 34.6 ohm
|   slope of the pullup table from 0 to 0.27 V, typ, clamps not added: 36.2 ohm
|   rising waveform, R_fixture 50.000, V_fixture 0.0: 20-80 % time 123ps typ, 141ps min, 112ps max; typ from 0 V to 1.03 V
|   rising waveform, R_fixture 50.000, V_fixture 1.800: 20-80 % time 91.8ps typ, 101ps min, 87.5ps max; typ from 0.739 V to 1.8 V
|   falling waveform, R_fixture 50.000, V_fixture 1.800: 20-80 % time 113ps typ, 140ps min, 104ps max; typ from 1.8 V to 0.739 V
|   falling waveform, R_fixture 50.000, V_fixture 0.0: 20-80 % time 97.1ps typ, 114ps min, 91.5ps max; typ from 1.03 V to 0 V
[Pulldown]
|Voltage   I(typ)   I(min)   I(max)
-1.8V     -3.298A    -3.281A    -3.33A
-1.195V   -462.3mA   -536mA     -422.7mA
-1.14V    -284.1mA   -361.4mA   -238.7mA
-1.03V    -88.26mA   -132.4mA   -69.8mA
-920mV    -51.08mA   -59.01mA   -48.25mA
2.435V    69.71mA    68.94mA    66.66mA
2.71V     90.14mA    141.1mA    84.18mA
2.82V     149.9mA    378.2mA    95.45mA
2.875V    265.2mA    596.5mA    118.8mA
2.93V     470.7mA    866.3mA    206.4mA
2.985V    746.3mA    1.174A     405.4mA
3.6V      5.053A     5.452A     4.686A
[Pullup]
|Voltage   I(typ)   I(min)   I(max)
-1.8V     5.02A      5.05A      5.033A
-1.13V    431.5mA    583.9mA    343.4mA
-1.075V   223.3mA    358.5mA    150.8mA
-1.02V    105.1mA    198.2mA    68.9mA
-910mV    43.31mA    61.95mA    40.92mA
-360mV    10.31mA    10.63mA    10.22mA
2.445V    -58.49mA   -61.98mA   -56.41mA
2.665V    -76.78mA   -88.13mA   -73.23mA
2.83V     -118.7mA   -241.7mA   -90.66mA
2.885V    -185.2mA   -374mA     -105.9mA
2.995V    -489mA     -743.3mA   -283.8mA
3.6V      -3.316A    -3.546A    -3.096A
[Ramp]
| variable   typ   min   max
dV/dt_r   0.621/0.123n   0.596/0.141n   0.643/0.112n
dV/dt_f   0.636/0.113n   0.612/0.140n   0.642/0.104n
R_load = 50.000
[Rising Waveform]
R_fixture= 50.000
V_fixture= 0.0
V_fixture_min= 0.0
V_fixture_max= 0.0
|time   V(typ)   V(min)   V(max)
0s        2.161uV    12.94uV    933nV
420ps     -647.6uV   -273.4uV   -155.3uV
475ps     11.03mV    -1.043mV   120.9mV
544ps     246.3mV    62.59mV    535.4mV
589ps     505mV      224.1mV    793mV
623ps     687.7mV    384.9mV    912.8mV
713ps     942.2mV    765.5mV    1.034V
824ps     1.014V     933.8mV    1.064V
1.203ns   1.034V     990.8mV    1.072V
10ns      1.035V     992.6mV    1.072V
[Rising Waveform]
R_fixture= 50.000
V_fixture= 1.800
V_fixture_min= 1.750
V_fixture_max= 1.850
|time   V(typ)   V(min)   V(max)
0s        739.2mV    729.6mV    780.2mV
439ps     740.5mV    729.4mV    790.2mV
478ps     758.4mV    732.8mV    905.8mV
518ps     883.4mV    753.2mV    1.241V
547ps     1.1V       821.9mV    1.469V
573ps     1.317V     959.7mV    1.613V
628ps     1.616V     1.344V     1.767V
692ps     1.743V     1.613V     1.823V
773ps     1.785V     1.715V     1.843V
10ns      1.8V       1.75V      1.85V
[Falling Waveform]
R_fixture= 50.000
V_fixture= 1.800
V_fixture_min= 1.750
V_fixture_max= 1.850
|time   V(typ)   V(min)   V(max)
0s        1.8V       1.75V      1.85V
438ps     1.804V     1.751V     1.856V
492ps     1.792V     1.754V     1.737V
555ps     1.57V      1.674V     1.339V
596ps     1.322V     1.521V     1.075V
633ps     1.094V     1.343V     935.2mV
724ps     821.6mV    950.3mV    816.2mV
824ps     760.3mV    789.2mV    789.8mV
1.245ns   739.8mV    731.7mV    780.4mV
10ns      739.2mV    729.6mV    780.2mV
[Falling Waveform]
R_fixture= 50.000
V_fixture= 0.0
V_fixture_min= 0.0
V_fixture_max= 0.0
|time   V(typ)   V(min)   V(max)
0s        1.035V     992.5mV    1.072V
440ps     1.039V     994mV      1.077V
485ps     1.027V     997.7mV    951.2mV
512ps     951.9mV    986.7mV    758.6mV
543ps     769.2mV    919.5mV    506.1mV
606ps     329.3mV    578.3mV    157.2mV
646ps     156.3mV    355.2mV    72.31mV
696ps     59.08mV    163.8mV    29.52mV
790ps     12.06mV    30.8mV     6.8mV
10ns      2.294uV    13.13uV    988.6nV
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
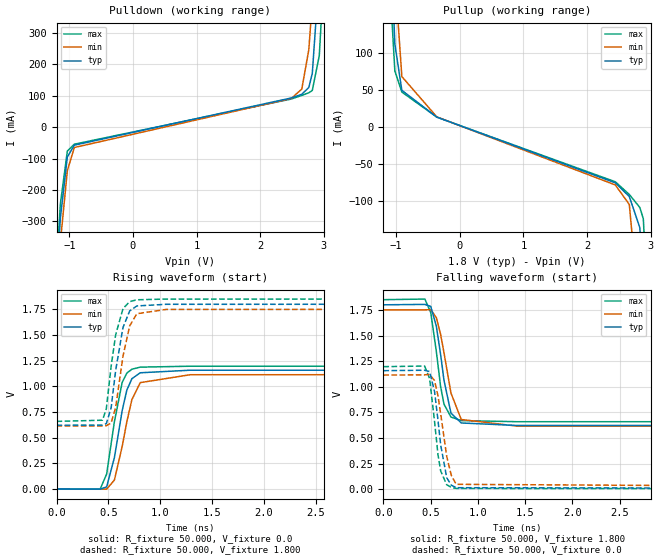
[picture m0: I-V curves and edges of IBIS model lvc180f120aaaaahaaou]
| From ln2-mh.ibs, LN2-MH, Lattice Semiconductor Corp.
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|   Model lvc180f120aaaaahaaou
[Model] lvc180f120aaaaahaaou
Model_type Output
Polarity   Non-Inverting
Enable   Active-High
Vmeas =  0.900V
Cref =  0.0F
Rref =  1.000M
Vref =  0.0V
C_comp   2.000pF   1.500pF   2.500pF
[Temperature Range]   25.000   0.125k   -40.000
[Voltage Range]   1.800V   1.750V   1.850V
[C Comp Corner]
C_comp   2.000pF   1.500pF   2.500pF
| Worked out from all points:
|   slope of the pulldown table from 0 to 0.27 V, typ, clamps not added: 26.2 ohm
|   slope of the pullup table from 0 to 0.27 V, typ, clamps not added: 27.4 ohm
|   rising waveform, R_fixture 50.000, V_fixture 0.0: 20-80 % time 122ps typ, 139ps min, 111ps max; typ from 0 V to 1.16 V
|   rising waveform, R_fixture 50.000, V_fixture 1.800: 20-80 % time 103ps typ, 108ps min, 97.6ps max; typ from 0.621 V to 1.8 V
|   falling waveform, R_fixture 50.000, V_fixture 1.800: 20-80 % time 113ps typ, 137ps min, 102ps max; typ from 1.8 V to 0.621 V
|   falling waveform, R_fixture 50.000, V_fixture 0.0: 20-80 % time 92ps typ, 110ps min, 84.9ps max; typ from 1.16 V to 0 V
[Pulldown]
|Voltage   I(typ)   I(min)   I(max)
-1.8V     -3.306A    -3.288A    -3.337A
-1.195V   -469.3mA   -542.6mA   -429.4mA
-1.14V    -291mA     -367.8mA   -245.3mA
-1.03V    -94.88mA   -138.6mA   -76.19mA
-920mV    -57.41mA   -64.95mA   -54.37mA
2.49V     93.02mA    91.52mA    89.69mA
2.655V    104.8mA    121.5mA    101.1mA
2.765V    126.4mA    246.6mA    109.6mA
2.82V     171.5mA    398.5mA    116.9mA
2.93V     492.7mA    886.7mA    228.3mA
2.985V    768.4mA    1.194A     427.5mA
3.6V      5.075A     5.471A     4.708A
[Pullup]
|Voltage   I(typ)   I(min)   I(max)
-1.8V     5.026A     5.056A     5.041A
-1.13V    438.5mA    590.7mA    350.6mA
-1.075V   230.2mA    365.2mA    157.8mA
-1.02V    111.8mA    204.8mA    75.64mA
-910mV    49.6mA     68.14mA    47.26mA
-360mV    13.51mA    13.77mA    13.45mA
2.445V    -75.02mA   -77.89mA   -73.6mA
2.665V    -93.51mA   -104.2mA   -90.72mA
2.83V     -135.4mA   -257.8mA   -108.2mA
2.885V    -202mA     -390mA     -123.4mA
2.995V    -505.6mA   -759.1mA   -301.3mA
3.6V      -3.33A     -3.558A    -3.111A
[Ramp]
| variable   typ   min   max
dV/dt_r   0.694/0.122n   0.669/0.139n   0.718/0.111n
dV/dt_f   0.707/0.113n   0.681/0.137n   0.715/0.102n
R_load = 50.000
[Rising Waveform]
R_fixture= 50.000
V_fixture= 0.0
V_fixture_min= 0.0
V_fixture_max= 0.0
|time   V(typ)   V(min)   V(max)
0s        1.783uV    10.71uV    772.3nV
421ps     -789.4uV   -316.9uV   -251.6uV
483ps     20.14mV    -1.544mV   145.7mV
558ps     306.2mV    87.87mV    656.4mV
633ps     765mV      414.8mV    1.039V
678ps     964.1mV    656.4mV    1.129V
727ps     1.075V     871.4mV    1.167V
807ps     1.132V     1.036V     1.187V
1.288ns   1.157V     1.113V     1.196V
10ns      1.157V     1.114V     1.196V
[Rising Waveform]
R_fixture= 50.000
V_fixture= 1.800
V_fixture_min= 1.750
V_fixture_max= 1.850
|time   V(typ)   V(min)   V(max)
0s        621.4mV    614.4mV    658.5mV
443ps     622.4mV    614.2mV    670.1mV
480ps     636.8mV    617mV      781.6mV
526ps     788.3mV    642.7mV    1.191V
570ps     1.155V     794.5mV    1.502V
641ps     1.574V     1.295V     1.757V
705ps     1.734V     1.588V     1.825V
774ps     1.783V     1.707V     1.843V
1.056ns   1.799V     1.749V     1.85V
10ns      1.8V       1.75V      1.85V
[Falling Waveform]
R_fixture= 50.000
V_fixture= 1.800
V_fixture_min= 1.750
V_fixture_max= 1.850
|time   V(typ)   V(min)   V(max)
0s        1.8V       1.75V      1.85V
439ps     1.804V     1.751V     1.856V
501ps     1.784V     1.753V     1.724V
560ps     1.592V     1.675V     1.346V
605ps     1.317V     1.513V     1.005V
641ps     1.064V     1.333V     830.4mV
715ps     742.4mV    938.1mV    704.3mV
824ps     646.2mV    680.1mV    669.5mV
1.414ns   621.8mV    615.7mV    658.7mV
10ns      621.3mV    614.4mV    658.5mV
[Falling Waveform]
R_fixture= 50.000
V_fixture= 0.0
V_fixture_min= 0.0
V_fixture_max= 0.0
|time   V(typ)   V(min)   V(max)
0s        1.157V     1.114V     1.196V
436ps     1.161V     1.116V     1.202V
489ps     1.148V     1.12V      1.08V
541ps     955.3mV    1.06V      663.5mV
577ps     678.3mV    914.4mV    341.6mV
606ps     433mV      736.4mV    178.4mV
670ps     112.1mV    320.1mV    43.22mV
719ps     38.35mV    133.5mV    16.92mV
771ps     14.39mV    47.16mV    7.18mV
10ns      1.916uV    10.96uV    826nV
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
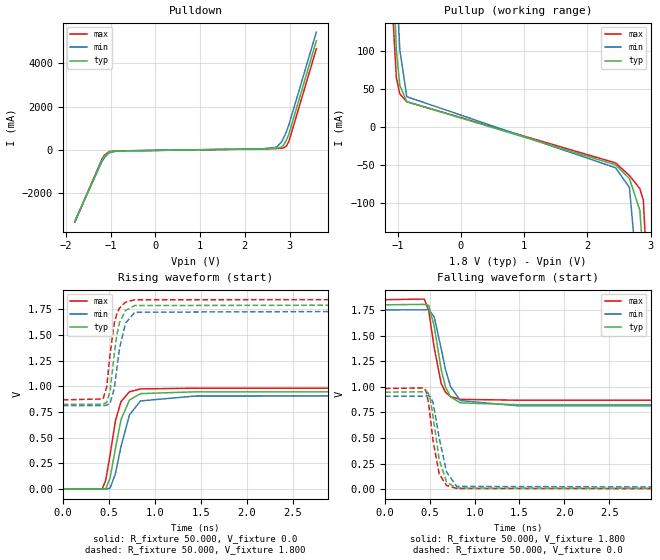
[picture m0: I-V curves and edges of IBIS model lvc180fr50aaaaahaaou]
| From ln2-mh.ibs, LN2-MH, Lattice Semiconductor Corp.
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|   Model lvc180fr50aaaaahaaou
[Model] lvc180fr50aaaaahaaou
Model_type Output
Polarity   Non-Inverting
Enable   Active-High
Vmeas =  0.900V
Cref =  0.0F
Rref =  1.000M
Vref =  0.0V
C_comp   2.000pF   1.500pF   2.500pF
[Temperature Range]   25.000   0.125k   -40.000
[Voltage Range]   1.800V   1.750V   1.850V
[C Comp Corner]
C_comp   2.000pF   1.500pF   2.500pF
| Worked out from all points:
|   slope of the pulldown table from 0 to 0.27 V, typ, clamps not added: 41.9 ohm
|   slope of the pullup table from 0 to 0.27 V, typ, clamps not added: 43.7 ohm
|   rising waveform, R_fixture 50.000, V_fixture 0.0: 20-80 % time 126ps typ, 146ps min, 114ps max; typ from 0 V to 0.947 V
|   rising waveform, R_fixture 50.000, V_fixture 1.800: 20-80 % time 86.8ps typ, 98.6ps min, 82.3ps max; typ from 0.824 V to 1.8 V
|   falling waveform, R_fixture 50.000, V_fixture 1.800: 20-80 % time 120ps typ, 148ps min, 110ps max; typ from 1.8 V to 0.824 V
|   falling waveform, R_fixture 50.000, V_fixture 0.0: 20-80 % time 101ps typ, 118ps min, 95.8ps max; typ from 0.947 V to 0 V
[Pulldown]
|Voltage   I(typ)   I(min)   I(max)
-1.8V     -3.294A    -3.278A    -3.326A
-1.195V   -458.5mA   -532.4mA   -419mA
-1.14V    -280.3mA   -357.8mA   -235mA
-1.03V    -84.65mA   -128.9mA   -66.27mA
-865mV    -41.07mA   -44.27mA   -39.11mA
2.38V     55.95mA    55.75mA    53.07mA
2.71V     78.46mA    130.2mA    72.51mA
2.82V     138mA      367.2mA    83.51mA
2.875V    253.2mA    585.4mA    106.7mA
2.93V     458.5mA    855.2mA    194.2mA
2.985V    734.1mA    1.163A     393mA
3.6V      5.042A     5.441A     4.674A
[Pullup]
|Voltage   I(typ)   I(min)   I(max)
-1.8V     5.016A     5.047A     5.029A
-1.13V    427.6mA    580.3mA    339.5mA
-1.075V   219.6mA    354.9mA    147mA
-1.02V    101.5mA    194.7mA    65.19mA
-965mV    55.05mA    102.1mA    43.91mA
-855mV    33.72mA    40.18mA    33.49mA
2.445V    -49.7mA    -53.59mA   -47.21mA
2.665V    -67.88mA   -79.69mA   -63.86mA
2.83V     -109.8mA   -233.3mA   -81.28mA
2.885V    -176.4mA   -365.6mA   -96.53mA
2.995V    -480.1mA   -735mA     -274.4mA
3.6V      -3.309A    -3.539A    -3.088A
[Ramp]
| variable   typ   min   max
dV/dt_r   0.568/0.127n   0.544/0.146n   0.589/0.114n
dV/dt_f   0.585/0.121n   0.562/0.148n   0.589/0.110n
R_load = 50.000
[Rising Waveform]
R_fixture= 50.000
V_fixture= 0.0
V_fixture_min= 0.0
V_fixture_max= 0.0
|time   V(typ)   V(min)   V(max)
0s        2.43uV     14.53uV    1.048uV
429ps     -769.7uV   -411.8uV   2.905mV
467ps     3.519mV    -930.5uV   88.96mV
514ps     109.8mV    10.06mV    335.7mV
572ps     398.1mV    150.7mV    666.9mV
632ps     675.4mV    414.2mV    851.5mV
724ps     867mV      722.3mV    947.6mV
844ps     929.2mV    858.1mV    975.1mV
1.442ns   946.9mV    906.2mV    982.4mV
10ns      947mV      906.6mV    982.4mV
[Rising Waveform]
R_fixture= 50.000
V_fixture= 1.800
V_fixture_min= 1.750
V_fixture_max= 1.850
|time   V(typ)   V(min)   V(max)
0s        824.4mV    813.3mV    868.6mV
437ps     825.7mV    813.1mV    877.4mV
477ps     843.8mV    816.8mV    995.7mV
514ps     954.5mV    836mV      1.32V
560ps     1.325V     984.7mV    1.619V
586ps     1.498V     1.168V     1.704V
616ps     1.621V     1.369V     1.763V
681ps     1.739V     1.615V     1.82V
781ps     1.787V     1.722V     1.843V
10ns      1.8V       1.75V      1.85V
[Falling Waveform]
R_fixture= 50.000
V_fixture= 1.800
V_fixture_min= 1.750
V_fixture_max= 1.850
|time   V(typ)   V(min)   V(max)
0s        1.8V       1.75V      1.85V
438ps     1.804V     1.751V     1.856V
488ps     1.794V     1.754V     1.744V
549ps     1.59V      1.682V     1.381V
627ps     1.167V     1.371V     1.031V
675ps     997mV      1.168V     946.1mV
731ps     900.9mV    1.001V     902.8mV
841ps     842.7mV    865mV      876.8mV
1.481ns   824.5mV    813.7mV    868.6mV
10ns      824.4mV    813.3mV    868.5mV
[Falling Waveform]
R_fixture= 50.000
V_fixture= 0.0
V_fixture_min= 0.0
V_fixture_max= 0.0
|time   V(typ)   V(min)   V(max)
0s        947mV      906.6mV    982.4mV
434ps     950.9mV    907.7mV    988.7mV
460ps     953.2mV    909.9mV    957mV
482ps     941mV      911.6mV    861.8mV
508ps     869.4mV    902.6mV    680.8mV
537ps     703.8mV    843.8mV    468.4mV
605ps     286.6mV    499mV      147.8mV
687ps     68.62mV    167.1mV    36.46mV
799ps     11.8mV     27.34mV    6.926mV
10ns      2.556uV    14.67uV    1.108uV
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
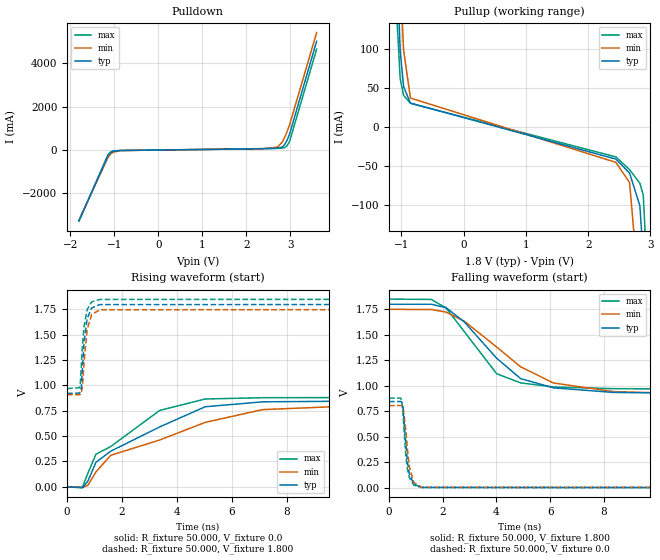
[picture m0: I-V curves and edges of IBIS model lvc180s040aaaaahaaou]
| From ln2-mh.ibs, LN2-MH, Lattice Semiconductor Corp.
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|   Model lvc180s040aaaaahaaou
[Model] lvc180s040aaaaahaaou
Model_type Output
Polarity   Non-Inverting
Enable   Active-High
Vmeas =  0.900V
Cref =  0.0F
Rref =  1.000M
Vref =  0.0V
C_comp   2.000pF   1.500pF   2.500pF
[Temperature Range]   25.000   0.125k   -40.000
[Voltage Range]   1.800V   1.750V   1.850V
[C Comp Corner]
C_comp   2.000pF   1.500pF   2.500pF
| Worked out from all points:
|   slope of the pulldown table from 0 to 0.27 V, typ, clamps not added: 52 ohm
|   slope of the pullup table from 0 to 0.27 V, typ, clamps not added: 54.3 ohm
|   rising waveform, R_fixture 50.000, V_fixture 0.0: 20-80 % time 2.99ns typ, 4.05ns min, 2.32ns max; typ from 0 V to 0.846 V
|   rising waveform, R_fixture 50.000, V_fixture 1.800: 20-80 % time 160ps typ, 169ps min, 158ps max; typ from 0.922 V to 1.8 V
|   falling waveform, R_fixture 50.000, V_fixture 1.800: 20-80 % time 1.92ns typ, 2.52ns min, 1.48ns max; typ from 1.8 V to 0.922 V
|   falling waveform, R_fixture 50.000, V_fixture 0.0: 20-80 % time 172ps typ, 185ps min, 165ps max; typ from 0.846 V to 0 V
[Pulldown]
|Voltage   I(typ)   I(min)   I(max)
-1.8V     -3.291A    -3.274A    -3.322A
-1.14V    -276.9mA   -354.6mA   -231.7mA
-1.085V   -149.1mA   -217.6mA   -111.5mA
-1.03V    -81.34mA   -125.8mA   -63.07mA
-865mV    -37.99mA   -41.38mA   -36.12mA
2.38V     46.17mA    46.47mA    43.45mA
2.71V     67.87mA    120.2mA    62.04mA
2.82V     127.2mA    357.1mA    72.79mA
2.875V    242.3mA    575.2mA    95.86mA
2.93V     447.5mA    845mA      183.2mA
2.985V    723mA      1.153A     382mA
3.6V      5.031A     5.432A     4.663A
[Pullup]
|Voltage   I(typ)   I(min)   I(max)
-1.8V     5.013A     5.045A     5.026A
-1.13V    424.1mA    576.9mA    336mA
-1.075V   216.1mA    351.6mA    143.6mA
-1.02V    98.11mA    191.4mA    61.81mA
-965mV    51.8mA     98.91mA    40.64mA
-855mV    30.69mA    37.2mA     30.43mA
2.445V    -41.43mA   -45.63mA   -38.61mA
2.665V    -59.52mA   -71.66mA   -55.11mA
2.83V     -101.4mA   -225.3mA   -72.51mA
2.885V    -168mA     -357.6mA   -87.76mA
2.995V    -471.8mA   -727.1mA   -265.7mA
3.6V      -3.302A    -3.533A    -3.08A
[Ramp]
| variable   typ   min   max
dV/dt_r   0.507/2.998n   0.484/4.052n   0.528/2.324n
dV/dt_f   0.527/1.923n   0.505/2.523n   0.529/1.477n
R_load = 50.000
[Rising Waveform]
R_fixture= 50.000
V_fixture= 0.0
V_fixture_min= 0.0
V_fixture_max= 0.0
|time   V(typ)   V(min)   V(max)
0s        2.741uV    16.36uV    1.179uV
558ps     -9.935mV   -5.303mV   -5.037mV
758ps     56.9mV     15.47mV    135.2mV
1.051ns   242.5mV    147.4mV    321.8mV
1.589ns   351.6mV    311mV      397.6mV
3.37ns    590.7mV    461.8mV    753.2mV
5.026ns   789.4mV    635.6mV    865.8mV
7.109ns   837.8mV    760.9mV    878.5mV
10.69ns   845.3mV    801.4mV    879.8mV
50ns      845.7mV    806.3mV    879.8mV
[Rising Waveform]
R_fixture= 50.000
V_fixture= 1.800
V_fixture_min= 1.750
V_fixture_max= 1.850
|time   V(typ)   V(min)   V(max)
0s        921.8mV    908.1mV    968mV
449ps     923.8mV    908.1mV    976.8mV
483ps     934.6mV    911.8mV    1.022V
519ps     984.3mV    925.4mV    1.201V
558ps     1.165V     986.9mV    1.393V
616ps     1.421V     1.226V     1.577V
729ps     1.656V     1.549V     1.746V
893ps     1.763V     1.698V     1.823V
1.189ns   1.796V     1.745V     1.847V
50ns      1.8V       1.75V      1.85V
[Falling Waveform]
R_fixture= 50.000
V_fixture= 1.800
V_fixture_min= 1.750
V_fixture_max= 1.850
|time   V(typ)   V(min)   V(max)
0s        1.8V       1.75V      1.85V
1.573ns   1.8V       1.748V     1.847V
2.126ns   1.766V     1.723V     1.763V
2.804ns   1.626V     1.633V     1.531V
4.005ns   1.271V     1.381V     1.119V
4.897ns   1.071V     1.187V     1.029V
6.117ns   980.4mV    1.028V     988.8mV
8.356ns   935.4mV    943.7mV    972.1mV
12.23ns   923.6mV    914.7mV    968.4mV
50ns      921.8mV    908.1mV    968mV
[Falling Waveform]
R_fixture= 50.000
V_fixture= 0.0
V_fixture_min= 0.0
V_fixture_max= 0.0
|time   V(typ)   V(min)   V(max)
0s        845.7mV    806.3mV    879.8mV
440ps     846.4mV    806.7mV    879.3mV
484ps     839mV      807.6mV    832.3mV
522ps     786.3mV    797.6mV    723.5mV
628ps     425.2mV    564.6mV    309mV
686ps     255mV      378.5mV    185.8mV
757ps     138.2mV    208.1mV    101.3mV
924ps     34.84mV    51.71mV    25.85mV
1.216ns   4.209mV    5.881mV    3.351mV
50ns      2.772uV    16.32uV    1.198uV
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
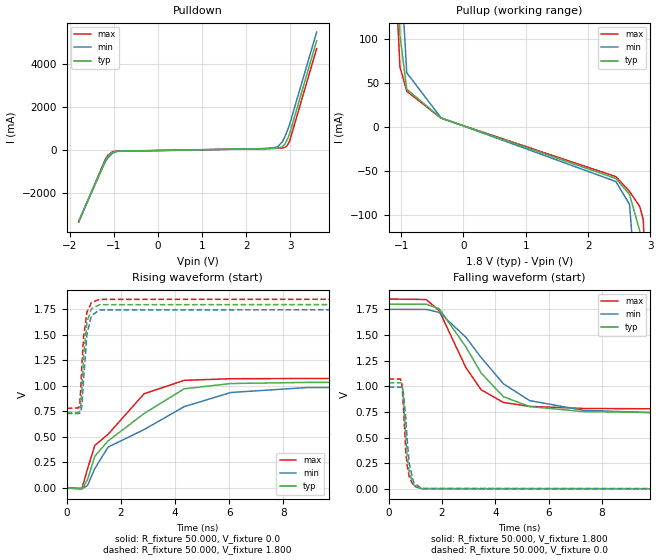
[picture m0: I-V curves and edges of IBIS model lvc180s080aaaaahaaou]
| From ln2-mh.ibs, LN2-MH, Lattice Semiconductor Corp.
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|   Model lvc180s080aaaaahaaou
[Model] lvc180s080aaaaahaaou
Model_type Output
Polarity   Non-Inverting
Enable   Active-High
Vmeas =  0.900V
Cref =  0.0F
Rref =  1.000M
Vref =  0.0V
C_comp   2.000pF   1.500pF   2.500pF
[Temperature Range]   25.000   0.125k   -40.000
[Voltage Range]   1.800V   1.750V   1.850V
[C Comp Corner]
C_comp   2.000pF   1.500pF   2.500pF
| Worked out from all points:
|   slope of the pulldown table from 0 to 0.27 V, typ, clamps not added: 34.6 ohm
|   slope of the pullup table from 0 to 0.27 V, typ, clamps not added: 36.2 ohm
|   rising waveform, R_fixture 50.000, V_fixture 0.0: 20-80 % time 2.38ns typ, 3.27ns min, 1.83ns max; typ from 0 V to 1.03 V
|   rising waveform, R_fixture 50.000, V_fixture 1.800: 20-80 % time 168ps typ, 174ps min, 165ps max; typ from 0.739 V to 1.8 V
|   falling waveform, R_fixture 50.000, V_fixture 1.800: 20-80 % time 1.62ns typ, 2.07ns min, 1.27ns max; typ from 1.8 V to 0.739 V
|   falling waveform, R_fixture 50.000, V_fixture 0.0: 20-80 % time 169ps typ, 183ps min, 163ps max; typ from 1.03 V to 0 V
[Pulldown]
|Voltage   I(typ)   I(min)   I(max)
-1.8V     -3.298A    -3.281A    -3.33A
-1.195V   -462.3mA   -536mA     -422.7mA
-1.14V    -284.1mA   -361.4mA   -238.7mA
-1.03V    -88.26mA   -132.4mA   -69.8mA
-920mV    -51.08mA   -59.01mA   -48.25mA
2.435V    69.71mA    68.94mA    66.66mA
2.71V     90.14mA    141.1mA    84.17mA
2.82V     149.9mA    378.2mA    95.45mA
2.875V    265.2mA    596.4mA    118.8mA
2.93V     470.7mA    866.3mA    206.4mA
2.985V    746.3mA    1.174A     405.4mA
3.6V      5.053A     5.452A     4.686A
[Pullup]
|Voltage   I(typ)   I(min)   I(max)
-1.8V     5.02A      5.05A      5.033A
-1.13V    431.5mA    583.9mA    343.4mA
-1.075V   223.3mA    358.5mA    150.8mA
-1.02V    105.1mA    198.2mA    68.9mA
-910mV    43.31mA    61.95mA    40.92mA
-360mV    10.31mA    10.63mA    10.22mA
2.445V    -58.49mA   -61.97mA   -56.41mA
2.665V    -76.78mA   -88.13mA   -73.23mA
2.83V     -118.7mA   -241.7mA   -90.66mA
2.885V    -185.2mA   -374mA     -105.9mA
2.995V    -489mA     -743.3mA   -283.8mA
3.6V      -3.316A    -3.546A    -3.096A
[Ramp]
| variable   typ   min   max
dV/dt_r   0.621/2.377n   0.596/3.274n   0.643/1.837n
dV/dt_f   0.636/1.623n   0.612/2.069n   0.642/1.268n
R_load = 50.000
[Rising Waveform]
R_fixture= 50.000
V_fixture= 0.0
V_fixture_min= 0.0
V_fixture_max= 0.0
|time   V(typ)   V(min)   V(max)
0s        2.161uV    12.94uV    933nV
564ps     -11.67mV   -7.068mV   -3.872mV
768ps     83.88mV    24.9mV     189.9mV
1.036ns   311.8mV    190.7mV    416.5mV
1.526ns   460.6mV    400.5mV    526.3mV
2.857ns   729.6mV    572.4mV    923.3mV
4.333ns   971mV      796.3mV    1.054V
6.059ns   1.023V     935.2mV    1.07V
8.909ns   1.034V     984mV      1.072V
50ns      1.035V     992.5mV    1.072V
[Rising Waveform]
R_fixture= 50.000
V_fixture= 1.800
V_fixture_min= 1.750
V_fixture_max= 1.850
|time   V(typ)   V(min)   V(max)
0s        739.2mV    729.6mV    780.2mV
438ps     739.4mV    729mV      784.6mV
483ps     755.1mV    732.7mV    834.3mV
522ps     813.7mV    749.5mV    1.008V
562ps     988.4mV    818.1mV    1.225V
621ps     1.287V     1.065V     1.479V
746ps     1.625V     1.507V     1.723V
911ps     1.755V     1.688V     1.817V
1.208ns   1.795V     1.744V     1.847V
50ns      1.8V       1.75V      1.85V
[Falling Waveform]
R_fixture= 50.000
V_fixture= 1.800
V_fixture_min= 1.750
V_fixture_max= 1.850
|time   V(typ)   V(min)   V(max)
0s        1.8V       1.75V      1.85V
1.404ns   1.8V       1.749V     1.846V
1.891ns   1.757V     1.721V     1.738V
2.894ns   1.385V     1.479V     1.184V
3.467ns   1.13V      1.281V     967.3mV
4.304ns   900mV      1.025V     843.9mV
5.284ns   803.9mV    862mV      805.3mV
7.321ns   754.6mV    766.9mV    785.4mV
11.02ns   741.2mV    736.3mV    780.7mV
50ns      739.2mV    729.6mV    780.2mV
[Falling Waveform]
R_fixture= 50.000
V_fixture= 0.0
V_fixture_min= 0.0
V_fixture_max= 0.0
|time   V(typ)   V(min)   V(max)
0s        1.035V     992.5mV    1.072V
448ps     1.035V     992.7mV    1.071V
493ps     1.026V     993.9mV    1.021V
532ps     966.9mV    981mV      892.8mV
642ps     504.8mV    691.8mV    363.1mV
697ps     309.7mV    469.2mV    224.3mV
771ps     163.6mV    249.7mV    119.2mV
935ps     42.3mV     63.5mV     31.3mV
1.227ns   5.337mV    7.313mV    4.37mV
50ns      2.195uV    12.94uV    950.8nV
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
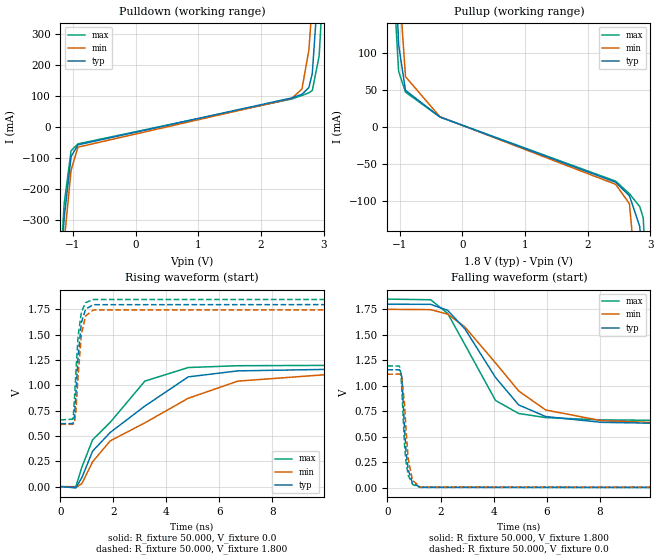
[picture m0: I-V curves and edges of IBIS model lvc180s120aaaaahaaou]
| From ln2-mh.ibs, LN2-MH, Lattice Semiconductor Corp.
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|   Model lvc180s120aaaaahaaou
[Model] lvc180s120aaaaahaaou
Model_type Output
Polarity   Non-Inverting
Enable   Active-High
Vmeas =  0.900V
Cref =  0.0F
Rref =  1.000M
Vref =  0.0V
C_comp   2.000pF   1.500pF   2.500pF
[Temperature Range]   25.000   0.125k   -40.000
[Voltage Range]   1.800V   1.750V   1.850V
[C Comp Corner]
C_comp   2.000pF   1.500pF   2.500pF
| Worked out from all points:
|   slope of the pulldown table from 0 to 0.27 V, typ, clamps not added: 26.2 ohm
|   slope of the pullup table from 0 to 0.27 V, typ, clamps not added: 27.4 ohm
|   rising waveform, R_fixture 50.000, V_fixture 0.0: 20-80 % time 2.71ns typ, 3.79ns min, 2.06ns max; typ from 0 V to 1.16 V
|   rising waveform, R_fixture 50.000, V_fixture 1.800: 20-80 % time 189ps typ, 191ps min, 182ps max; typ from 0.621 V to 1.8 V
|   falling waveform, R_fixture 50.000, V_fixture 1.800: 20-80 % time 1.84ns typ, 2.29ns min, 1.43ns max; typ from 1.8 V to 0.621 V
|   falling waveform, R_fixture 50.000, V_fixture 0.0: 20-80 % time 169ps typ, 184ps min, 163ps max; typ from 1.16 V to 0 V
[Pulldown]
|Voltage   I(typ)   I(min)   I(max)
-1.8V     -3.306A    -3.288A    -3.337A
-1.195V   -469.3mA   -542.6mA   -429.4mA
-1.14V    -291mA     -367.8mA   -245.3mA
-1.03V    -94.88mA   -138.6mA   -76.19mA
-920mV    -57.41mA   -64.94mA   -54.37mA
2.49V     93.01mA    91.51mA    89.69mA
2.655V    104.8mA    121.5mA    101.1mA
2.765V    126.4mA    246.6mA    109.6mA
2.82V     171.5mA    398.5mA    116.9mA
2.93V     492.7mA    886.7mA    228.3mA
2.985V    768.4mA    1.194A     427.5mA
3.6V      5.075A     5.471A     4.708A
[Pullup]
|Voltage   I(typ)   I(min)   I(max)
-1.8V     5.026A     5.056A     5.041A
-1.13V    438.5mA    590.7mA    350.6mA
-1.075V   230.2mA    365.2mA    157.8mA
-1.02V    111.8mA    204.8mA    75.64mA
-910mV    49.6mA     68.14mA    47.26mA
-360mV    13.51mA    13.77mA    13.45mA
2.445V    -75.02mA   -77.89mA   -73.59mA
2.665V    -93.51mA   -104.2mA   -90.72mA
2.83V     -135.4mA   -257.7mA   -108.2mA
2.885V    -202mA     -390mA     -123.4mA
2.995V    -505.6mA   -759.1mA   -301.3mA
3.6V      -3.33A     -3.558A    -3.111A
[Ramp]
| variable   typ   min   max
dV/dt_r   0.694/2.717n   0.669/3.799n   0.718/2.060n
dV/dt_f   0.707/1.844n   0.681/2.301n   0.715/1.433n
R_load = 50.000
[Rising Waveform]
R_fixture= 50.000
V_fixture= 0.0
V_fixture_min= 0.0
V_fixture_max= 0.0
|time   V(typ)   V(min)   V(max)
0s        1.783uV    10.71uV    772.3nV
580ps     -12.25mV   -8.797mV   -474.2uV
807ps     87.73mV    29.61mV    190.5mV
1.213ns   350mV      244.8mV    462.3mV
1.876ns   533.9mV    451.1mV    633.6mV
3.185ns   794.9mV    629.1mV    1.041V
4.823ns   1.083V     871.8mV    1.175V
6.694ns   1.142V     1.041V     1.193V
9.874ns   1.156V     1.102V     1.196V
50ns      1.157V     1.114V     1.196V
[Rising Waveform]
R_fixture= 50.000
V_fixture= 1.800
V_fixture_min= 1.750
V_fixture_max= 1.850
|time   V(typ)   V(min)   V(max)
0s        621.4mV    614.4mV    658.5mV
452ps     622.3mV    614mV      665.3mV
489ps     633.3mV    617.7mV    709.9mV
536ps     714.7mV    639.5mV    905.2mV
584ps     917.7mV    749.3mV    1.131V
664ps     1.271V     1.079V     1.478V
790ps     1.619V     1.505V     1.723V
950ps     1.752V     1.684V     1.816V
1.241ns   1.795V     1.743V     1.846V
50ns      1.8V       1.75V      1.85V
[Falling Waveform]
R_fixture= 50.000
V_fixture= 1.800
V_fixture_min= 1.750
V_fixture_max= 1.850
|time   V(typ)   V(min)   V(max)
0s        1.8V       1.75V      1.85V
1.629ns   1.799V     1.747V     1.844V
2.269ns   1.74V      1.703V     1.71V
2.918ns   1.558V     1.577V     1.404V
4.069ns   1.082V     1.225V     856.9mV
4.939ns   813.1mV    949.9mV    729.1mV
5.959ns   698.7mV    763.1mV    688.6mV
8.058ns   642.2mV    658.3mV    666mV
12.05ns   624.4mV    622.8mV    659.3mV
50ns      621.3mV    614.4mV    658.5mV
[Falling Waveform]
R_fixture= 50.000
V_fixture= 0.0
V_fixture_min= 0.0
V_fixture_max= 0.0
|time   V(typ)   V(min)   V(max)
0s        1.157V     1.114V     1.196V
453ps     1.158V     1.115V     1.194V
505ps     1.142V     1.115V     1.13V
542ps     1.083V     1.098V     983.6mV
650ps     581.6mV    810.8mV    404mV
707ps     350.8mV    554.2mV    244.6mV
786ps     176.6mV    285.2mV    124.3mV
947ps     46.41mV    73.39mV    33.3mV
1.237ns   5.808mV    8.302mV    4.636mV
50ns      1.817uV    10.76uV    788.3nV
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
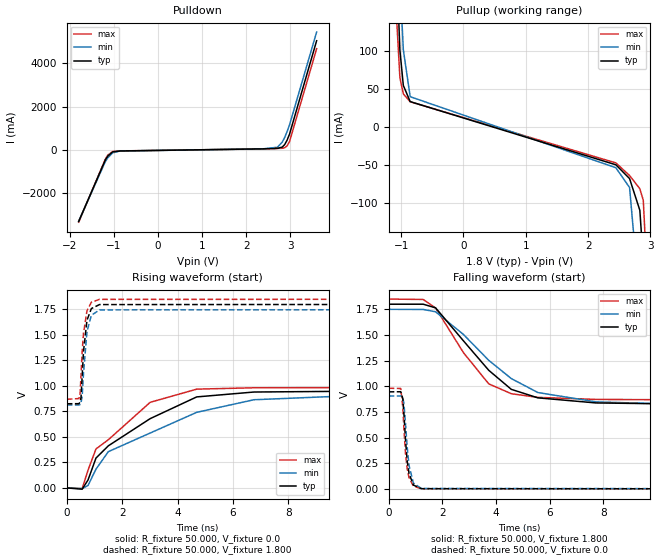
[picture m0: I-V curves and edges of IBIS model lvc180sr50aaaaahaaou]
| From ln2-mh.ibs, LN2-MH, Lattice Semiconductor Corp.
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|   Model lvc180sr50aaaaahaaou
[Model] lvc180sr50aaaaahaaou
Model_type Output
Polarity   Non-Inverting
Enable   Active-High
Vmeas =  0.900V
Cref =  0.0F
Rref =  1.000M
Vref =  0.0V
C_comp   2.000pF   1.500pF   2.500pF
[Temperature Range]   25.000   0.125k   -40.000
[Voltage Range]   1.800V   1.750V   1.850V
[C Comp Corner]
C_comp   2.000pF   1.500pF   2.500pF
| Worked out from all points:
|   slope of the pulldown table from 0 to 0.27 V, typ, clamps not added: 41.9 ohm
|   slope of the pullup table from 0 to 0.27 V, typ, clamps not added: 43.7 ohm
|   rising waveform, R_fixture 50.000, V_fixture 0.0: 20-80 % time 2.57ns typ, 3.49ns min, 1.98ns max; typ from 0 V to 0.947 V
|   rising waveform, R_fixture 50.000, V_fixture 1.800: 20-80 % time 160ps typ, 168ps min, 157ps max; typ from 0.824 V to 1.8 V
|   falling waveform, R_fixture 50.000, V_fixture 1.800: 20-80 % time 1.94ns typ, 2.44ns min, 1.53ns max; typ from 1.8 V to 0.824 V
|   falling waveform, R_fixture 50.000, V_fixture 0.0: 20-80 % time 170ps typ, 182ps min, 164ps max; typ from 0.947 V to 0 V
[Pulldown]
|Voltage   I(typ)   I(min)   I(max)
-1.8V     -3.294A    -3.278A    -3.326A
-1.195V   -458.5mA   -532.4mA   -419mA
-1.14V    -280.3mA   -357.8mA   -235mA
-1.03V    -84.65mA   -128.9mA   -66.27mA
-865mV    -41.07mA   -44.27mA   -39.11mA
2.38V     55.95mA    55.75mA    53.07mA
2.71V     78.46mA    130.2mA    72.51mA
2.82V     138mA      367.2mA    83.51mA
2.875V    253.2mA    585.4mA    106.7mA
2.93V     458.5mA    855.2mA    194.2mA
2.985V    734.1mA    1.163A     393mA
3.6V      5.042A     5.441A     4.674A
[Pullup]
|Voltage   I(typ)   I(min)   I(max)
-1.8V     5.016A     5.047A     5.029A
-1.13V    427.6mA    580.3mA    339.5mA
-1.075V   219.6mA    354.9mA    147mA
-1.02V    101.5mA    194.7mA    65.19mA
-965mV    55.05mA    102.1mA    43.91mA
-855mV    33.72mA    40.18mA    33.49mA
2.445V    -49.69mA   -53.59mA   -47.21mA
2.665V    -67.88mA   -79.69mA   -63.86mA
2.83V     -109.8mA   -233.3mA   -81.28mA
2.885V    -176.4mA   -365.6mA   -96.53mA
2.995V    -480.1mA   -735mA     -274.4mA
3.6V      -3.309A    -3.539A    -3.088A
[Ramp]
| variable   typ   min   max
dV/dt_r   0.568/2.569n   0.544/3.494n   0.590/1.985n
dV/dt_f   0.585/1.949n   0.562/2.451n   0.589/1.536n
R_load = 50.000
[Rising Waveform]
R_fixture= 50.000
V_fixture= 0.0
V_fixture_min= 0.0
V_fixture_max= 0.0
|time   V(typ)   V(min)   V(max)
0s        2.43uV     14.53uV    1.048uV
557ps     -12.31mV   -6.846mV   -6.764mV
768ps     77.71mV    24.2mV     174.2mV
1.055ns   292.4mV    183.6mV    381.8mV
1.501ns   412.3mV    355.2mV    471.8mV
3.011ns   678.4mV    537.4mV    838.2mV
4.694ns   891.5mV    740.4mV    967.6mV
6.762ns   939.3mV    863.8mV    981mV
10.12ns   946.6mV    901.5mV    982.4mV
50ns      947mV      906.6mV    982.4mV
[Rising Waveform]
R_fixture= 50.000
V_fixture= 1.800
V_fixture_min= 1.750
V_fixture_max= 1.850
|time   V(typ)   V(min)   V(max)
0s        824.4mV    813.3mV    868.6mV
441ps     825.1mV    812.8mV    875.1mV
483ps     841.7mV    817.1mV    930.4mV
515ps     887.3mV    831.9mV    1.106V
558ps     1.102V     907.8mV    1.345V
604ps     1.336V     1.121V     1.514V
729ps     1.642V     1.53V      1.735V
888ps     1.757V     1.691V     1.819V
1.182ns   1.796V     1.744V     1.847V
50ns      1.8V       1.75V      1.85V
[Falling Waveform]
R_fixture= 50.000
V_fixture= 1.800
V_fixture_min= 1.750
V_fixture_max= 1.850
|time   V(typ)   V(min)   V(max)
0s        1.8V       1.75V      1.85V
1.287ns   1.8V       1.749V     1.846V
1.749ns   1.764V     1.726V     1.763V
2.787ns   1.443V     1.505V     1.328V
3.727ns   1.157V     1.254V     1.025V
4.569ns   971.2mV    1.076V     928.8mV
5.559ns   888.6mV    940.3mV    893.1mV
7.726ns   839.1mV    849.5mV    873.4mV
11.5ns    826.4mV    819.9mV    869mV
50ns      824.4mV    813.3mV    868.5mV
[Falling Waveform]
R_fixture= 50.000
V_fixture= 0.0
V_fixture_min= 0.0
V_fixture_max= 0.0
|time   V(typ)   V(min)   V(max)
0s        947mV      906.5mV    982.4mV
450ps     948mV      907mV      979.6mV
526ps     881.1mV    897.4mV    796.2mV
572ps     718.3mV    822mV      567.5mV
629ps     469.4mV    631.7mV    340.7mV
690ps     274.1mV    409.1mV    199.6mV
757ps     153.9mV    232mV      112.8mV
921ps     39.86mV    59.11mV    29.63mV
1.219ns   4.825mV    6.567mV    3.933mV
50ns      2.461uV    14.51uV    1.066uV
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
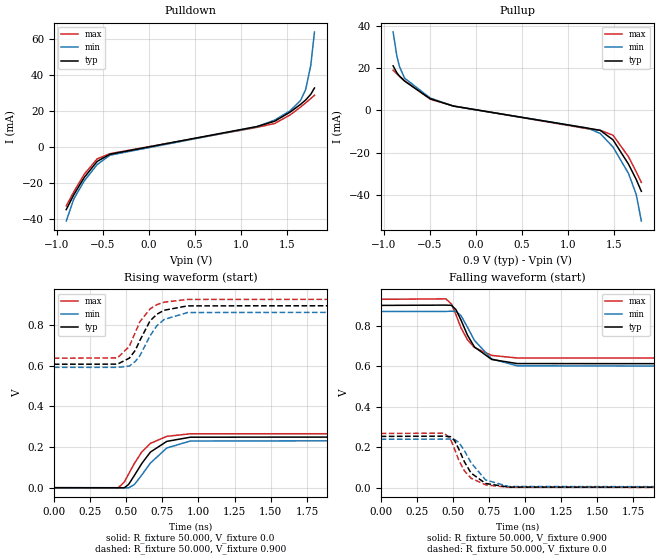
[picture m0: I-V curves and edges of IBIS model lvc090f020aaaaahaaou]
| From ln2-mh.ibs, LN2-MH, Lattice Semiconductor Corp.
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|   Model lvc090f020aaaaahaaou
[Model] lvc090f020aaaaahaaou
Model_type Output
Polarity   Non-Inverting
Enable   Active-High
Vmeas =  0.500V
Cref =  0.0F
Rref =  1.000M
Vref =  0.0V
C_comp   2.000pF   1.500pF   2.500pF
[Temperature Range]   25.000   0.125k   -40.000
[Voltage Range]   0.900V   0.870V   0.930V
[C Comp Corner]
C_comp   2.000pF   1.500pF   2.500pF
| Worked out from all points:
|   slope of the pulldown table from 0 to 0.135 V, typ, clamps not added: 104 ohm
|   slope of the pullup table from 0 to 0.135 V, typ, clamps not added: 120 ohm
|   rising waveform, R_fixture 50.000, V_fixture 0.0: 20-80 % time 164ps typ, 178ps min, 155ps max; typ from 0 V to 0.254 V
|   rising waveform, R_fixture 50.000, V_fixture 0.900: 20-80 % time 137ps typ, 143ps min, 129ps max; typ from 0.608 V to 0.9 V
|   falling waveform, R_fixture 50.000, V_fixture 0.900: 20-80 % time 139ps typ, 158ps min, 131ps max; typ from 0.9 V to 0.608 V
|   falling waveform, R_fixture 50.000, V_fixture 0.0: 20-80 % time 122ps typ, 136ps min, 117ps max; typ from 0.254 V to 0 V
[Pulldown]
|Voltage   I(typ)   I(min)   I(max)
-900mV    -35.05mA   -41.37mA   -33.01mA
-816mV    -26.61mA   -28.93mA   -24.96mA
-704mV    -17.15mA   -19.04mA   -15.35mA
-564mV    -8.249mA   -10.01mA   -6.839mA
-424mV    -4.234mA   -4.768mA   -3.923mA
1.172V    11.12mA    11mA       10.66mA
1.368V    14.11mA    14.76mA    12.86mA
1.536V    19.19mA    19.93mA    17.62mA
1.648V    23.45mA    25.61mA    21.94mA
1.704V    25.9mA     31.66mA    24.28mA
1.76V     29.1mA     45.2mA     26.72mA
1.8V      32.57mA    63.68mA    28.56mA
[Pullup]
|Voltage   I(typ)   I(min)   I(max)
-900mV    21.13mA    37.17mA    19.14mA
-860mV    17.9mA     25.96mA    17.35mA
-832mV    16.3mA     20.93mA    16.23mA
-776mV    13.92mA    15.33mA    14.12mA
-496mV    5.51mA     5.845mA    5.301mA
-244mV    2.038mA    2.025mA    2.093mA
1.212V    -8.41mA    -8.347mA   -8.679mA
1.352V    -9.458mA   -10.92mA   -9.426mA
1.492V    -13.97mA   -17.4mA    -11.78mA
1.66V     -25.48mA   -29.88mA   -21.98mA
1.744V    -32.73mA   -39.79mA   -29.08mA
1.8V      -38.4mA    -52.48mA   -34.18mA
[Ramp]
| variable   typ   min   max
dV/dt_r   0.152/0.164n   0.144/0.178n   0.161/0.155n
dV/dt_f   0.175/0.139n   0.166/0.158n   0.175/0.131n
R_load = 50.000
[Rising Waveform]
R_fixture= 50.000
V_fixture= 0.0
V_fixture_min= 0.0
V_fixture_max= 0.0
|time   V(typ)   V(min)   V(max)
0s        1.59uV     11.12uV    702.6nV
445ps     -345.4uV   -1.708uV   -734.1uV
488ps     -243.8uV   -444.9uV   28.44mV
517ps     16.13mV    -590.6uV   67.52mV
557ps     60.33mV    15.39mV    119.4mV
609ps     120mV      63.34mV    176.9mV
668ps     175.5mV    121.4mV    218.2mV
781ps     228.1mV    195.6mV    252.9mV
944ps     248.7mV    229.9mV    265.5mV
10ns      253.8mV    239.6mV    268.4mV
[Rising Waveform]
R_fixture= 50.000
V_fixture= 0.900
V_fixture_min= 0.870
V_fixture_max= 0.930
|time   V(typ)   V(min)   V(max)
0s        608.1mV    592.6mV    637.7mV
440ps     608.5mV    592.6mV    639.3mV
522ps     638mV      598.9mV    696.1mV
563ps     676.2mV    621.7mV    764.6mV
596ps     726.8mV    651.1mV    818.5mV
665ps     821.2mV    747.4mV    880.5mV
712ps     854mV      797.4mV    901.2mV
763ps     874mV      828.7mV    913.8mV
925ps     895.5mV    862.7mV    927.2mV
10ns      900mV      870mV      930mV
[Falling Waveform]
R_fixture= 50.000
V_fixture= 0.900
V_fixture_min= 0.870
V_fixture_max= 0.930
|time   V(typ)   V(min)   V(max)
0s        900mV      870mV      930mV
452ps     901.4mV    870.2mV    932.2mV
491ps     900.2mV    871.4mV    906.3mV
522ps     879.1mV    869.7mV    853.7mV
557ps     827.6mV    849.5mV    789.7mV
602ps     753mV      792.2mV    730.2mV
650ps     695.2mV    727.5mV    692.4mV
770ps     633.3mV    635.9mV    653.2mV
947ps     613.1mV    601.9mV    640.6mV
10ns      608.1mV    592.6mV    637.7mV
[Falling Waveform]
R_fixture= 50.000
V_fixture= 0.0
V_fixture_min= 0.0
V_fixture_max= 0.0
|time   V(typ)   V(min)   V(max)
0s        253.8mV    239.6mV    268.3mV
440ps     255mV      240.3mV    269.7mV
484ps     252.6mV    240.7mV    241mV
512ps     233.6mV    238.8mV    191.4mV
543ps     189.5mV    223.7mV    134.5mV
581ps     127.9mV    183.1mV    83.29mV
627ps     72.65mV    123.5mV    47.45mV
728ps     21.62mV    38.78mV    14.57mV
888ps     3.731mV    6.576mV    2.582mV
10ns      1.605uV    11.15uV    726.7nV
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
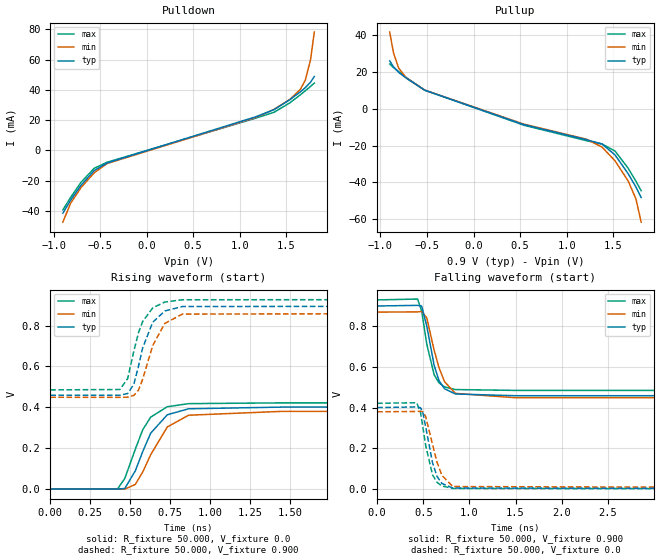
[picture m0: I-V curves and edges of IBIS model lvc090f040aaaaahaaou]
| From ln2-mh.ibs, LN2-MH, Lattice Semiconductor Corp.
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|   Model lvc090f040aaaaahaaou
[Model] lvc090f040aaaaahaaou
Model_type Output
Polarity   Non-Inverting
Enable   Active-High
Vmeas =  0.500V
Cref =  0.0F
Rref =  1.000M
Vref =  0.0V
C_comp   2.000pF   1.500pF   2.500pF
[Temperature Range]   25.000   0.125k   -40.000
[Voltage Range]   0.900V   0.870V   0.930V
[C Comp Corner]
C_comp   2.000pF   1.500pF   2.500pF
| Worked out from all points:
|   slope of the pulldown table from 0 to 0.135 V, typ, clamps not added: 51.9 ohm
|   slope of the pullup table from 0 to 0.135 V, typ, clamps not added: 60.2 ohm
|   rising waveform, R_fixture 50.000, V_fixture 0.0: 20-80 % time 141ps typ, 159ps min, 130ps max; typ from 0 V to 0.401 V
|   rising waveform, R_fixture 50.000, V_fixture 0.900: 20-80 % time 101ps typ, 115ps min, 96ps max; typ from 0.459 V to 0.9 V
|   falling waveform, R_fixture 50.000, V_fixture 0.900: 20-80 % time 124ps typ, 156ps min, 113ps max; typ from 0.9 V to 0.459 V
|   falling waveform, R_fixture 50.000, V_fixture 0.0: 20-80 % time 112ps typ, 136ps min, 105ps max; typ from 0.401 V to 0 V
[Pulldown]
|Voltage   I(typ)   I(min)   I(max)
-900mV    -41.53mA   -47.43mA   -39.32mA
-816mV    -32.84mA   -34.79mA   -31.03mA
-704mV    -22.98mA   -24.51mA   -21.03mA
-564mV    -13.38mA   -14.84mA   -11.84mA
-424mV    -8.3mA     -8.676mA   -7.812mA
1.172V    22.19mA    21.73mA    21.28mA
1.368V    26.9mA     27.12mA    25.18mA
1.536V    33.39mA    33.62mA    31.34mA
1.648V    38.57mA    40.09mA    36.58mA
1.704V    41.46mA    46.41mA    39.38mA
1.76V     45.06mA    59.95mA    42.27mA
1.8V      48.75mA    78.12mA    44.42mA
[Pullup]
|Voltage   I(typ)   I(min)   I(max)
-900mV    26.05mA    41.68mA    24.32mA
-860mV    22.78mA    30.49mA    22.46mA
-804mV    19.81mA    22.11mA    20.17mA
-720mV    16.54mA    16.65mA    16.92mA
-524mV    10.09mA    10.13mA    10.1mA
540mV     -8.627mA   -8.324mA   -8.925mA
1.212V    -16.8mA    -16.53mA   -17.34mA
1.38V     -19.15mA   -20.8mA    -19.14mA
1.52V     -25.14mA   -28.36mA   -23.02mA
1.66V     -35.27mA   -39.2mA    -32.28mA
1.744V    -42.55mA   -49.08mA   -39.42mA
1.8V      -48.2mA    -61.64mA   -44.53mA
[Ramp]
| variable   typ   min   max
dV/dt_r   0.241/0.141n   0.228/0.159n   0.253/0.130n
dV/dt_f   0.264/0.124n   0.253/0.156n   0.267/0.113n
R_load = 50.000
[Rising Waveform]
R_fixture= 50.000
V_fixture= 0.0
V_fixture_min= 0.0
V_fixture_max= 0.0
|time   V(typ)   V(min)   V(max)
0s        1.166uV    8.276uV    518.6nV
420ps     -449.2uV   -243.3uV   -236.7uV
466ps     2.573mV    -736.2uV   51.56mV
532ps     89.26mV    22.59mV    195.2mV
578ps     182.8mV    82.76mV    289.9mV
628ps     273.5mV    167.8mV    351.9mV
732ps     363.5mV    303.9mV    403mV
865ps     392.8mV    361.3mV    418mV
1.445ns   401mV      380.1mV    421.8mV
10ns      401mV      380.3mV    421.8mV
[Rising Waveform]
R_fixture= 50.000
V_fixture= 0.900
V_fixture_min= 0.870
V_fixture_max= 0.930
|time   V(typ)   V(min)   V(max)
0s        459.2mV    449.1mV    485.3mV
435ps     459.3mV    448.8mV    487.2mV
484ps     467.5mV    449.7mV    540.7mV
523ps     513.2mV    458.8mV    676.5mV
552ps     602mV      484.5mV    766.3mV
578ps     691.3mV    537.7mV    820mV
641ps     816.8mV    702.9mV    887mV
716ps     871.4mV    810.6mV    915.3mV
826ps     893.5mV    856.4mV    926.6mV
10ns      900mV      870mV      930mV
[Falling Waveform]
R_fixture= 50.000
V_fixture= 0.900
V_fixture_min= 0.870
V_fixture_max= 0.930
|time   V(typ)   V(min)   V(max)
0s        900mV      870mV      930mV
439ps     903.2mV    871.1mV    934.1mV
483ps     899.3mV    873.1mV    873.4mV
538ps     800.8mV    841.2mV    712mV
618ps     607.9mV    681.8mV    561.9mV
670ps     533.8mV    597.8mV    522.8mV
730ps     493.4mV    528.2mV    502.4mV
848ps     467.7mV    470.6mV    489.4mV
1.499ns   459.2mV    449.3mV    485.3mV
10ns      459.2mV    449.1mV    485.3mV
[Falling Waveform]
R_fixture= 50.000
V_fixture= 0.0
V_fixture_min= 0.0
V_fixture_max= 0.0
|time   V(typ)   V(min)   V(max)
0s        401mV      380.3mV    421.8mV
429ps     404mV      381.8mV    424.6mV
471ps     400.1mV    383mV      374.1mV
497ps     372.6mV    379.6mV    299.1mV
526ps     305.9mV    356.8mV    214.8mV
600ps     130.3mV    220.2mV    70.64mV
648ps     63.39mV    133.9mV    33.98mV
702ps     27.88mV    67.6mV     15.59mV
820ps     5.591mV    12.96mV    3.223mV
10ns      1.184uV    8.301uV    544.8nV
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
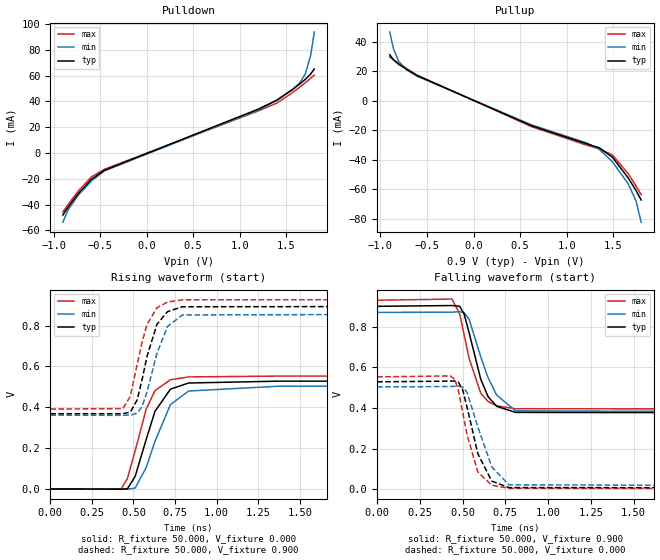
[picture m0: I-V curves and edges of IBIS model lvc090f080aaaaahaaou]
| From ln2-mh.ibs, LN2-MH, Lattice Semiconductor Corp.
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|   Model lvc090f080aaaaahaaou
[Model] lvc090f080aaaaahaaou
Model_type Output
Polarity   Non-Inverting
Enable   Active-High
Vmeas =  0.500V
Cref =  0.0F
Rref =  1.000M
Vref =  0.0V
C_comp   2.000pF   1.500pF   2.500pF
[Temperature Range]   25.000   0.125k   -40.000
[Voltage Range]   0.900V   0.870V   0.930V
[C Comp Corner]
C_comp   2.000pF   1.500pF   2.500pF
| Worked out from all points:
|   slope of the pulldown table from 0 to 0.135 V, typ, clamps not added: 34.6 ohm
|   slope of the pullup table from 0 to 0.135 V, typ, clamps not added: 34.8 ohm
|   rising waveform, R_fixture 50.000, V_fixture 0.000: 20-80 % time 124ps typ, 139ps min, 115ps max; typ from 0 V to 0.528 V
|   rising waveform, R_fixture 50.000, V_fixture 0.900: 20-80 % time 98.1ps typ, 109ps min, 93.6ps max; typ from 0.368 V to 0.9 V
|   falling waveform, R_fixture 50.000, V_fixture 0.900: 20-80 % time 105ps typ, 133ps min, 95.7ps max; typ from 0.9 V to 0.368 V
|   falling waveform, R_fixture 50.000, V_fixture 0.000: 20-80 % time 96.9ps typ, 119ps min, 89.4ps max; typ from 0.528 V to 0 V
[Pulldown]
|Voltage   I(typ)   I(min)   I(max)
-900mV    -48.1mA    -53.62mA   -45.71mA
-844mV    -41.93mA   -44.13mA   -39.95mA
-732mV    -31.3mA    -32.45mA   -29.24mA
-592mV    -20.3mA    -21.52mA   -18.46mA
-452mV    -13.33mA   -13.75mA   -12.52mA
1.2V      34.07mA    33.36mA    32.68mA
1.396V    40.94mA    40.74mA    38.62mA
1.564V    49.16mA    48.91mA    46.64mA
1.648V    53.79mA    54.71mA    51.32mA
1.704V    57.13mA    61.43mA    54.58mA
1.76V     61.17mA    75.35mA    57.92mA
1.8V      65.16mA    93.75mA    60.4mA
[Pullup]
|Voltage   I(typ)   I(min)   I(max)
-900mV    31.04mA    46.4mA     29.52mA
-860mV    27.69mA    35.14mA    27.6mA
-804mV    24.61mA    26.64mA    25.2mA
-720mV    21.15mA    20.98mA    21.75mA
-608mV    16.96mA    16.59mA    17.33mA
624mV     -17.11mA   -16.51mA   -17.72mA
1.212V    -29.24mA   -28.68mA   -30.18mA
1.352V    -32.09mA   -33.14mA   -32.74mA
1.492V    -38.49mA   -41.54mA   -36.92mA
1.66V     -52.37mA   -56.38mA   -49.5mA
1.744V    -60.84mA   -67.87mA   -57.83mA
1.8V      -67.4mA    -82.44mA   -63.77mA
[Ramp]
| variable   typ   min   max
dV/dt_r   0.317/0.124n   0.302/0.139n   0.332/0.115n
dV/dt_f   0.319/0.105n   0.305/0.133n   0.323/95.791p
R_load = 50.000
[Rising Waveform]
R_fixture = 50.000
V_fixture = 0.000
V_fixture_min = 0.000
V_fixture_max = 0.000
|  time   V(typ)   V(min)   V(max)
0s        1.752uV    7.1uV      1.201uV
426ps     -682.4uV   -390.4uV   1.071mV
463ps     530.6uV    -815.9uV   50.25mV
510ps     61.67mV    4.593mV    186.2mV
576ps     241.9mV    104.5mV    390.6mV
629ps     380.2mV    233.3mV    481.5mV
722ps     488.8mV    413mV      535.1mV
831ps     518.9mV    479.7mV    548.8mV
1.372ns   528.1mV    503.2mV    552.8mV
10ns      528.2mV    503.3mV    552.8mV
[Rising Waveform]
R_fixture = 50.000
V_fixture = 0.900
V_fixture_min = 0.870
V_fixture_max = 0.930
|  time   V(typ)   V(min)   V(max)
0s        368.5mV    361.2mV    391.4mV
436ps     368.4mV    360.8mV    393.8mV
481ps     376.6mV    361.6mV    453.6mV
522ps     436.1mV    371.1mV    609.2mV
552ps     537.1mV    404.6mV    721.1mV
582ps     651.5mV    478.4mV    807mV
641ps     806.6mV    664.2mV    887.2mV
704ps     868mV      795.3mV    915.3mV
794ps     892.4mV    852.2mV    926.4mV
10ns      900mV      870mV      930mV
[Falling Waveform]
R_fixture = 50.000
V_fixture = 0.900
V_fixture_min = 0.870
V_fixture_max = 0.930
|  time   V(typ)   V(min)   V(max)
0s        900mV      870mV      930mV
438ps     903.8mV    871.1mV    935.7mV
483ps     900mV      874mV      862.3mV
509ps     861.7mV    868.8mV    758.2mV
538ps     769.9mV    836.1mV    643.9mV
606ps     541.2mV    651.1mV    472.2mV
649ps     455mV      548.6mV    431.4mV
699ps     407.9mV    463.3mV    410.2mV
809ps     377.8mV    385.4mV    395.9mV
10ns      368.5mV    361.2mV    391.4mV
[Falling Waveform]
R_fixture = 50.000
V_fixture = 0.000
V_fixture_min = 0.000
V_fixture_max = 0.000
|  time   V(typ)   V(min)   V(max)
0s        528.2mV    503.3mV    552.8mV
428ps     531.9mV    505.1mV    557.4mV
454ps     532.5mV    506.5mV    540.6mV
475ps     526.9mV    507mV      486mV
500ps     489.8mV    502.5mV    380.3mV
526ps     403.6mV    476.5mV    266.9mV
589ps     174.6mV    306.2mV    84.44mV
670ps     39.96mV    110.4mV    19.74mV
770ps     7.799mV    21.36mV    4.232mV
10ns      1.752uV    7.1uV      1.201uV
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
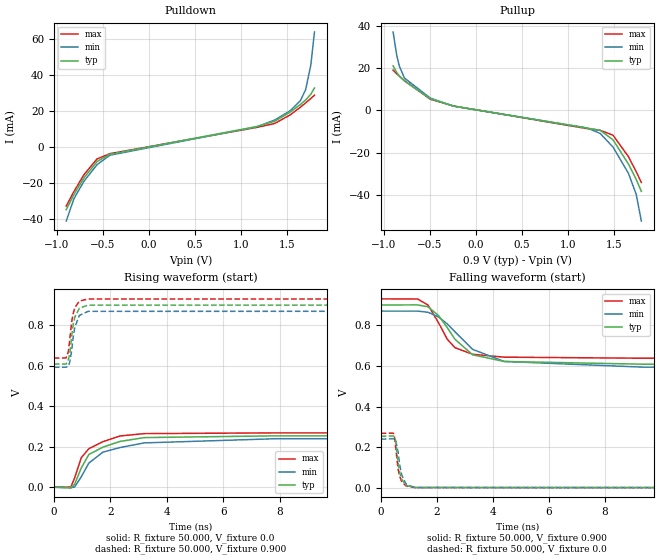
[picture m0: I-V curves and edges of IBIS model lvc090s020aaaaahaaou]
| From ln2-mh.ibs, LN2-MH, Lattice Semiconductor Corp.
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|   Model lvc090s020aaaaahaaou
[Model] lvc090s020aaaaahaaou
Model_type Output
Polarity   Non-Inverting
Enable   Active-High
Vmeas =  0.500V
Cref =  0.0F
Rref =  1.000M
Vref =  0.0V
C_comp   2.000pF   1.500pF   2.500pF
[Temperature Range]   25.000   0.125k   -40.000
[Voltage Range]   0.900V   0.870V   0.930V
[C Comp Corner]
C_comp   2.000pF   1.500pF   2.500pF
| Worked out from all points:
|   slope of the pulldown table from 0 to 0.135 V, typ, clamps not added: 104 ohm
|   slope of the pullup table from 0 to 0.135 V, typ, clamps not added: 120 ohm
|   rising waveform, R_fixture 50.000, V_fixture 0.0: 20-80 % time 989ps typ, 1.26ns min, 836ps max; typ from 0 V to 0.254 V
|   rising waveform, R_fixture 50.000, V_fixture 0.900: 20-80 % time 173ps typ, 179ps min, 166ps max; typ from 0.608 V to 0.9 V
|   falling waveform, R_fixture 50.000, V_fixture 0.900: 20-80 % time 1.02ns typ, 1.4ns min, 761ps max; typ from 0.9 V to 0.608 V
|   falling waveform, R_fixture 50.000, V_fixture 0.0: 20-80 % time 168ps typ, 178ps min, 164ps max; typ from 0.254 V to 0 V
[Pulldown]
|Voltage   I(typ)   I(min)   I(max)
-900mV    -35.05mA   -41.37mA   -33.01mA
-816mV    -26.61mA   -28.93mA   -24.96mA
-704mV    -17.15mA   -19.04mA   -15.35mA
-564mV    -8.249mA   -10.01mA   -6.839mA
-424mV    -4.234mA   -4.768mA   -3.923mA
1.172V    11.12mA    11mA       10.66mA
1.368V    14.11mA    14.76mA    12.86mA
1.536V    19.18mA    19.93mA    17.62mA
1.648V    23.45mA    25.61mA    21.94mA
1.704V    25.9mA     31.65mA    24.28mA
1.76V     29.1mA     45.2mA     26.72mA
1.8V      32.57mA    63.68mA    28.56mA
[Pullup]
|Voltage   I(typ)   I(min)   I(max)
-900mV    21.13mA    37.17mA    19.14mA
-860mV    17.9mA     25.96mA    17.35mA
-832mV    16.3mA     20.93mA    16.23mA
-776mV    13.92mA    15.33mA    14.12mA
-496mV    5.51mA     5.845mA    5.301mA
-244mV    2.038mA    2.025mA    2.093mA
1.212V    -8.409mA   -8.346mA   -8.679mA
1.352V    -9.458mA   -10.92mA   -9.426mA
1.492V    -13.97mA   -17.4mA    -11.78mA
1.66V     -25.48mA   -29.88mA   -21.98mA
1.744V    -32.73mA   -39.79mA   -29.08mA
1.8V      -38.4mA    -52.48mA   -34.18mA
[Ramp]
| variable   typ   min   max
dV/dt_r   0.152/0.987n   0.144/1.250n   0.161/0.835n
dV/dt_f   0.175/1.029n   0.166/1.411n   0.175/0.772n
R_load = 50.000
[Rising Waveform]
R_fixture= 50.000
V_fixture= 0.0
V_fixture_min= 0.0
V_fixture_max= 0.0
|time   V(typ)   V(min)   V(max)
0s        1.59uV     11.12uV    702.6nV
603ps     -3.092mV   -2.742mV   817.3uV
737ps     14.93mV    1.457mV    46.06mV
970ps     94.69mV    51.17mV    145.2mV
1.239ns   161.5mV    119.2mV    190.2mV
1.737ns   197.8mV    173.2mV    224.9mV
2.338ns   225.9mV    195.8mV    252.9mV
3.198ns   245mV      218.8mV    264.7mV
7.825ns   253.7mV    239.3mV    268.3mV
50ns      253.8mV    239.6mV    268.4mV
[Rising Waveform]
R_fixture= 50.000
V_fixture= 0.900
V_fixture_min= 0.870
V_fixture_max= 0.930
|time   V(typ)   V(min)   V(max)
0s        608.1mV    592.6mV    637.7mV
432ps     608.1mV    592.6mV    638.3mV
515ps     630.5mV    597mV      669.3mV
569ps     661.5mV    620.6mV    736.1mV
631ps     746mV      673.2mV    816.3mV
689ps     805.6mV    745.1mV    860.4mV
743ps     839.8mV    790.1mV    885.8mV
904ps     884mV      848.3mV    919.2mV
1.208ns   899mV      868.3mV    929.3mV
50ns      900mV      870mV      930mV
[Falling Waveform]
R_fixture= 50.000
V_fixture= 0.900
V_fixture_min= 0.870
V_fixture_max= 0.930
|time   V(typ)   V(min)   V(max)
0s        900mV      870mV      930mV
1.32ns    900.2mV    869.9mV    929.4mV
1.69ns    891mV      864.1mV    899.7mV
2.074ns   846.9mV    840.6mV    810.6mV
2.381ns   788mV      806.5mV    730.9mV
2.654ns   731mV      768mV      689.9mV
3.285ns   654.9mV    681.4mV    657.3mV
4.414ns   621.9mV    622mV      643.1mV
9.404ns   608.4mV    593.8mV    637.8mV
50ns      608.1mV    592.6mV    637.7mV
[Falling Waveform]
R_fixture= 50.000
V_fixture= 0.0
V_fixture_min= 0.0
V_fixture_max= 0.0
|time   V(typ)   V(min)   V(max)
0s        253.8mV    239.6mV    268.3mV
452ps     255.3mV    241.2mV    269mV
491ps     253.4mV    241mV      251.8mV
530ps     234.4mV    238.4mV    203mV
620ps     126.6mV    176.2mV    93.55mV
680ps     75.46mV    113.5mV    56.15mV
750ps     42.04mV    63.21mV    31.43mV
915ps     11.27mV    16.65mV    8.57mV
1.22ns    1.547mV    1.975mV    1.366mV
50ns      1.598uV    11.15uV    711.3nV
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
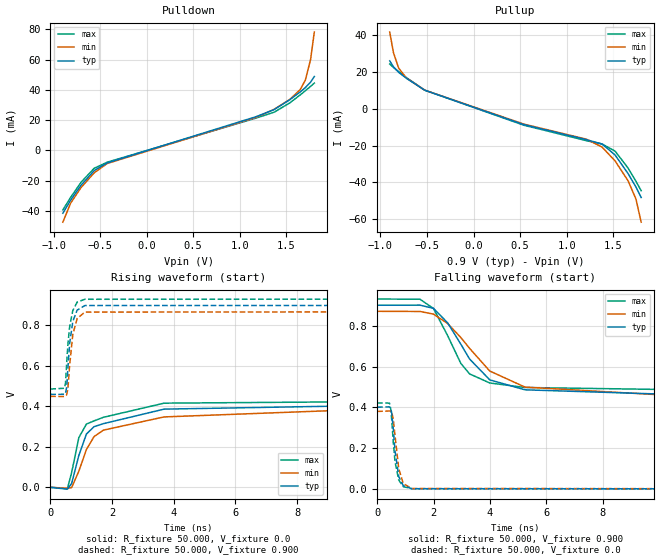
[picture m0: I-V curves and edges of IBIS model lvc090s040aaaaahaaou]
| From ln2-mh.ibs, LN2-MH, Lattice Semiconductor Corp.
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|   Model lvc090s040aaaaahaaou
[Model] lvc090s040aaaaahaaou
Model_type Output
Polarity   Non-Inverting
Enable   Active-High
Vmeas =  0.500V
Cref =  0.0F
Rref =  1.000M
Vref =  0.0V
C_comp   2.000pF   1.500pF   2.500pF
[Temperature Range]   25.000   0.125k   -40.000
[Voltage Range]   0.900V   0.870V   0.930V
[C Comp Corner]
C_comp   2.000pF   1.500pF   2.500pF
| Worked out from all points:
|   slope of the pulldown table from 0 to 0.135 V, typ, clamps not added: 51.9 ohm
|   slope of the pullup table from 0 to 0.135 V, typ, clamps not added: 60.2 ohm
|   rising waveform, R_fixture 50.000, V_fixture 0.0: 20-80 % time 1.07ns typ, 1.35ns min, 889ps max; typ from 0 V to 0.401 V
|   rising waveform, R_fixture 50.000, V_fixture 0.900: 20-80 % time 163ps typ, 173ps min, 161ps max; typ from 0.459 V to 0.9 V
|   falling waveform, R_fixture 50.000, V_fixture 0.900: 20-80 % time 1.34ns typ, 1.82ns min, 1.01ns max; typ from 0.9 V to 0.459 V
|   falling waveform, R_fixture 50.000, V_fixture 0.0: 20-80 % time 179ps typ, 196ps min, 171ps max; typ from 0.401 V to 0 V
[Pulldown]
|Voltage   I(typ)   I(min)   I(max)
-900mV    -41.53mA   -47.43mA   -39.32mA
-816mV    -32.84mA   -34.79mA   -31.03mA
-704mV    -22.98mA   -24.51mA   -21.03mA
-564mV    -13.38mA   -14.84mA   -11.84mA
-424mV    -8.3mA     -8.676mA   -7.812mA
1.172V    22.19mA    21.73mA    21.28mA
1.368V    26.9mA     27.12mA    25.18mA
1.536V    33.39mA    33.61mA    31.34mA
1.648V    38.57mA    40.09mA    36.58mA
1.704V    41.46mA    46.4mA     39.38mA
1.76V     45.06mA    59.95mA    42.27mA
1.8V      48.75mA    78.12mA    44.42mA
[Pullup]
|Voltage   I(typ)   I(min)   I(max)
-900mV    26.05mA    41.68mA    24.32mA
-860mV    22.78mA    30.49mA    22.46mA
-804mV    19.81mA    22.11mA    20.17mA
-720mV    16.54mA    16.64mA    16.92mA
-524mV    10.09mA    10.13mA    10.1mA
540mV     -8.627mA   -8.324mA   -8.925mA
1.212V    -16.8mA    -16.53mA   -17.34mA
1.38V     -19.15mA   -20.8mA    -19.14mA
1.52V     -25.14mA   -28.36mA   -23.02mA
1.66V     -35.27mA   -39.2mA    -32.28mA
1.744V    -42.55mA   -49.08mA   -39.42mA
1.8V      -48.2mA    -61.64mA   -44.53mA
[Ramp]
| variable   typ   min   max
dV/dt_r   0.241/1.064n   0.228/1.337n   0.253/0.885n
dV/dt_f   0.264/1.348n   0.253/1.828n   0.267/1.017n
R_load = 50.000
[Rising Waveform]
R_fixture= 50.000
V_fixture= 0.0
V_fixture_min= 0.0
V_fixture_max= 0.0
|time   V(typ)   V(min)   V(max)
0s        1.166uV    8.276uV    518.6nV
554ps     -9.246mV   -4.888mV   -6.655mV
691ps     18.5mV     -1.719mV   71.85mV
926ps     157.6mV    79.99mV    245.8mV
1.171ns   263.3mV    186.7mV    312.4mV
1.416ns   299.3mV    250.2mV    328mV
1.721ns   314.4mV    282.4mV    345.8mV
3.686ns   386.2mV    347.7mV    415.7mV
9.218ns   400.9mV    379.4mV    421.8mV
50ns      401mV      380.3mV    421.8mV
[Rising Waveform]
R_fixture= 50.000
V_fixture= 0.900
V_fixture_min= 0.870
V_fixture_max= 0.930
|time   V(typ)   V(min)   V(max)
0s        459.2mV    449.1mV    485.3mV
460ps     459.6mV    448.7mV    489.4mV
494ps     464.6mV    450.3mV    514.9mV
534ps     495.6mV    457.9mV    621.4mV
572ps     592.9mV    489.9mV    708.9mV
628ps     710.4mV    603.6mV    793.9mV
730ps     820mV      755.6mV    873mV
871ps     875.4mV    834mV      915.2mV
1.12ns    898mV      865.7mV    929mV
50ns      900mV      870mV      930mV
[Falling Waveform]
R_fixture= 50.000
V_fixture= 0.900
V_fixture_min= 0.870
V_fixture_max= 0.930
|time   V(typ)   V(min)   V(max)
0s        900mV      870mV      930mV
1.517ns   900.3mV    869.4mV    929.4mV
1.997ns   884.6mV    856.3mV    884.1mV
2.497ns   814.5mV    811.1mV    752.5mV
2.967ns   709.9mV    742.2mV    615.9mV
3.278ns   637.1mV    689.1mV    564.1mV
3.997ns   534.6mV    577.9mV    519.4mV
5.248ns   486mV      499.2mV    497.4mV
11.22ns   460.2mV    452.3mV    485.5mV
50ns      459.2mV    449.1mV    485.3mV
[Falling Waveform]
R_fixture= 50.000
V_fixture= 0.0
V_fixture_min= 0.0
V_fixture_max= 0.0
|time   V(typ)   V(min)   V(max)
0s        401mV      380.3mV    421.8mV
437ps     402.7mV    382.4mV    420.9mV
478ps     397.6mV    381.4mV    396.7mV
517ps     372.2mV    376.1mV    339.6mV
572ps     294mV      341.4mV    230.1mV
636ps     185.3mV    259.4mV    132mV
767ps     61.52mV    99.6mV     44.12mV
928ps     17mV       27.17mV    12.4mV
1.227ns   2.366mV    3.262mV    2.021mV
50ns      1.173uV    8.298uV    526.7nV
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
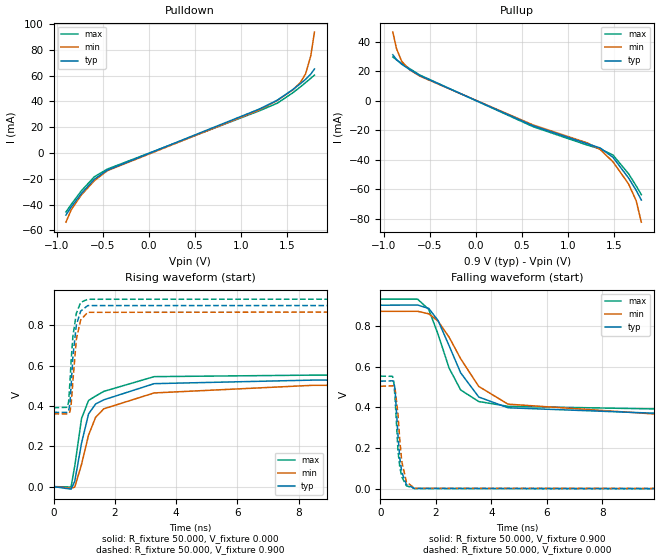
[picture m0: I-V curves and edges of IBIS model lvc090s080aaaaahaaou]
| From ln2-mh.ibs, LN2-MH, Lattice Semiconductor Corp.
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|   Model lvc090s080aaaaahaaou
[Model] lvc090s080aaaaahaaou
Model_type Output
Polarity   Non-Inverting
Enable   Active-High
Vmeas =  0.500V
Cref =  0.0F
Rref =  1.000M
Vref =  0.0V
C_comp   2.000pF   1.500pF   2.500pF
[Temperature Range]   25.000   0.125k   -40.000
[Voltage Range]   0.900V   0.870V   0.930V
[C Comp Corner]
C_comp   2.000pF   1.500pF   2.500pF
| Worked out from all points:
|   slope of the pulldown table from 0 to 0.135 V, typ, clamps not added: 34.6 ohm
|   slope of the pullup table from 0 to 0.135 V, typ, clamps not added: 34.8 ohm
|   rising waveform, R_fixture 50.000, V_fixture 0.000: 20-80 % time 729ps typ, 974ps min, 583ps max; typ from 0 V to 0.528 V
|   rising waveform, R_fixture 50.000, V_fixture 0.900: 20-80 % time 172ps typ, 178ps min, 168ps max; typ from 0.368 V to 0.9 V
|   falling waveform, R_fixture 50.000, V_fixture 0.900: 20-80 % time 1.16ns typ, 1.5ns min, 899ps max; typ from 0.9 V to 0.368 V
|   falling waveform, R_fixture 50.000, V_fixture 0.000: 20-80 % time 176ps typ, 193ps min, 168ps max; typ from 0.528 V to 0 V
[Pulldown]
|Voltage   I(typ)   I(min)   I(max)
-900mV    -48.1mA    -53.62mA   -45.71mA
-844mV    -41.93mA   -44.13mA   -39.95mA
-732mV    -31.3mA    -32.45mA   -29.24mA
-592mV    -20.3mA    -21.52mA   -18.46mA
-452mV    -13.33mA   -13.75mA   -12.52mA
1.2V      34.07mA    33.36mA    32.68mA
1.396V    40.94mA    40.74mA    38.62mA
1.564V    49.16mA    48.91mA    46.64mA
1.648V    53.79mA    54.71mA    51.32mA
1.704V    57.13mA    61.43mA    54.58mA
1.76V     61.17mA    75.34mA    57.92mA
1.8V      65.16mA    93.75mA    60.4mA
[Pullup]
|Voltage   I(typ)   I(min)   I(max)
-900mV    31.04mA    46.4mA     29.52mA
-860mV    27.69mA    35.14mA    27.6mA
-804mV    24.61mA    26.64mA    25.2mA
-720mV    21.15mA    20.98mA    21.75mA
-608mV    16.96mA    16.59mA    17.33mA
624mV     -17.11mA   -16.51mA   -17.72mA
1.212V    -29.24mA   -28.68mA   -30.18mA
1.352V    -32.09mA   -33.14mA   -32.74mA
1.492V    -38.49mA   -41.53mA   -36.92mA
1.66V     -52.37mA   -56.38mA   -49.5mA
1.744V    -60.84mA   -67.87mA   -57.83mA
1.8V      -67.4mA    -82.44mA   -63.77mA
[Ramp]
| variable   typ   min   max
dV/dt_r   0.317/0.725n   0.302/0.968n   0.332/0.579n
dV/dt_f   0.319/1.162n   0.305/1.504n   0.323/0.902n
R_load = 50.000
[Rising Waveform]
R_fixture = 50.000
V_fixture = 0.000
V_fixture_min = 0.000
V_fixture_max = 0.000
|  time   V(typ)   V(min)   V(max)
0s        1.752uV    7.396uV    1.201uV
572ps     -12.73mV   -8.073mV   -2.056mV
693ps     26.34mV    -2.445mV   102.4mV
913ps     214.9mV    109.5mV    337.4mV
1.143ns   360.4mV    255.5mV    427.1mV
1.373ns   409.7mV    343.5mV    449mV
1.64ns    430.4mV    385.7mV    472.2mV
3.284ns   510.5mV    464.5mV    545.3mV
8.459ns   528.1mV    502.3mV    552.8mV
50ns      528.2mV    503.3mV    552.8mV
[Rising Waveform]
R_fixture = 50.000
V_fixture = 0.900
V_fixture_min = 0.870
V_fixture_max = 0.930
|  time   V(typ)   V(min)   V(max)
0s        368.5mV    361.2mV    391.4mV
449ps     367.9mV    360.5mV    393.2mV
492ps     375.3mV    361.8mV    419.2mV
538ps     415.1mV    372.2mV    525.7mV
576ps     504.4mV    409.1mV    628.9mV
633ps     646.3mV    524.6mV    746.3mV
744ps     800.9mV    730mV      859.1mV
885ps     870mV      826.1mV    913.5mV
1.115ns   897.6mV    864.3mV    929mV
50ns      900mV      870mV      930mV
[Falling Waveform]
R_fixture = 50.000
V_fixture = 0.900
V_fixture_min = 0.870
V_fixture_max = 0.930
|  time   V(typ)   V(min)   V(max)
0s        900mV      870mV      930mV
1.342ns   900.7mV    870.1mV    929.5mV
1.743ns   884mV      857.9mV    879.1mV
2.076ns   825.4mV    822.3mV    758.2mV
2.476ns   701.5mV    743.5mV    592.2mV
2.892ns   569.1mV    637.8mV    485.3mV
3.543ns   450.8mV    502.6mV    428.6mV
4.597ns   398.2mV    415.9mV    405.2mV
10.25ns   369.6mV    364.4mV    391.6mV
50ns      368.5mV    361.2mV    391.4mV
[Falling Waveform]
R_fixture = 50.000
V_fixture = 0.000
V_fixture_min = 0.000
V_fixture_max = 0.000
|  time   V(typ)   V(min)   V(max)
0s        528.2mV    503.3mV    552.8mV
437ps     530.1mV    505.8mV    552mV
484ps     523.1mV    504.2mV    523.3mV
526ps     489.7mV    496.2mV    448.8mV
635ps     261.2mV    362.4mV    185.8mV
697ps     153.9mV    243.4mV    109.9mV
770ps     83.65mV    135.5mV    60.07mV
937ps     22.16mV    35.21mV    16.28mV
1.231ns   3.444mV    4.534mV    3.056mV
50ns      1.752uV    7.396uV    1.201uV
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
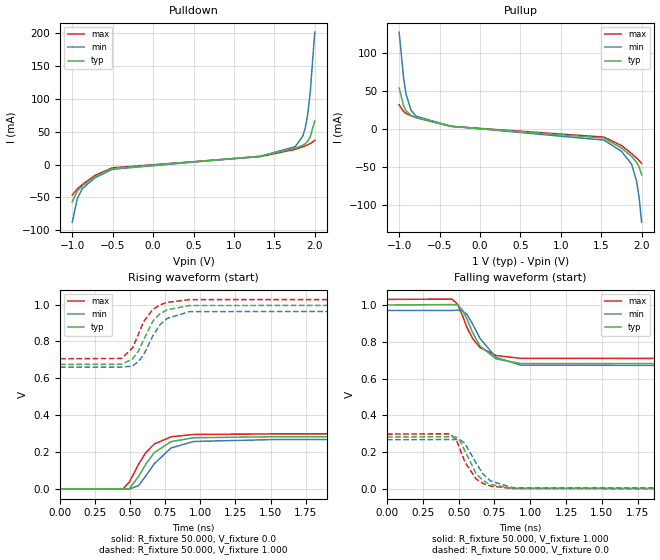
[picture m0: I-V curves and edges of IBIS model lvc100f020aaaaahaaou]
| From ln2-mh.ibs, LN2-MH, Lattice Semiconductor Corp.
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|   Model lvc100f020aaaaahaaou
[Model] lvc100f020aaaaahaaou
Model_type Output
Polarity   Non-Inverting
Enable   Active-High
Vmeas =  0.500V
Cref =  0.0F
Rref =  1.000M
Vref =  0.0V
C_comp   2.000pF   1.500pF   2.500pF
[Temperature Range]   25.000   0.125k   -40.000
[Voltage Range]   1.000V   0.970V   1.030V
[C Comp Corner]
C_comp   2.000pF   1.500pF   2.500pF
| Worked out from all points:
|   slope of the pulldown table from 0 to 0.15 V, typ, clamps not added: 104 ohm
|   slope of the pullup table from 0 to 0.15 V, typ, clamps not added: 119 ohm
|   rising waveform, R_fixture 50.000, V_fixture 0.0: 20-80 % time 164ps typ, 179ps min, 155ps max; typ from 0 V to 0.284 V
|   rising waveform, R_fixture 50.000, V_fixture 1.000: 20-80 % time 137ps typ, 143ps min, 128ps max; typ from 0.676 V to 1 V
|   falling waveform, R_fixture 50.000, V_fixture 1.000: 20-80 % time 139ps typ, 158ps min, 131ps max; typ from 1 V to 0.676 V
|   falling waveform, R_fixture 50.000, V_fixture 0.0: 20-80 % time 120ps typ, 134ps min, 117ps max; typ from 0.284 V to 0 V
[Pulldown]
|Voltage   I(typ)   I(min)   I(max)
-1V       -56.9mA    -88.01mA   -46.61mA
-938mV    -40.3mA    -52.1mA    -37.09mA
-876mV    -32.45mA   -36.85mA   -30.67mA
-721mV    -18.52mA   -20.39mA   -16.72mA
-504mV    -5.926mA   -7.266mA   -5.026mA
1.325V    12.55mA    12.61mA    12.01mA
1.759V    24.71mA    27.24mA    23.2mA
1.852V    29.35mA    43.2mA     27.18mA
1.883V    31.82mA    56.1mA     28.59mA
1.914V    35.72mA    77.32mA    30.13mA
1.945V    42.7mA     111.2mA    32mA
2V        66.34mA    202.1mA    36.97mA
[Pullup]
|Voltage   I(typ)   I(min)   I(max)
-1V       53.78mA    127.5mA    31.52mA
-945mV    30.36mA    66.68mA    22.72mA
-914mV    23.53mA    45.23mA    20.14mA
-852mV    17.48mA    24.38mA    17.1mA
-790mV    14.53mA    16.45mA    14.69mA
-356mV    3.112mA    3.321mA    3.089mA
1.535V    -12.25mA   -15.03mA   -11.05mA
1.752V    -25.62mA   -29.91mA   -22.18mA
1.876V    -36.63mA   -46.72mA   -32.81mA
1.938V    -44.29mA   -69.36mA   -38.7mA
1.969V    -50.45mA   -90.81mA   -41.95mA
2V        -60.71mA   -123.3mA   -45.82mA
[Ramp]
| variable   typ   min   max
dV/dt_r   0.170/0.164n   0.161/0.179n   0.179/0.155n
dV/dt_f   0.194/0.139n   0.185/0.158n   0.194/0.131n
R_load = 50.000
[Rising Waveform]
R_fixture= 50.000
V_fixture= 0.0
V_fixture_min= 0.0
V_fixture_max= 0.0
|time   V(typ)   V(min)   V(max)
0s        1.742uV    11.95uV    763.4nV
446ps     -397.2uV   -13.6uV    -728.7uV
493ps     1.15mV     -646.7uV   37.3mV
560ps     69.67mV    18.96mV    135.4mV
611ps     134.9mV    71.37mV    197.9mV
671ps     197.3mV    137.3mV    244mV
791ps     257mV      222.5mV    283.2mV
951ps     278.1mV    257.9mV    295.9mV
1.531ns   283.5mV    268.3mV    298.9mV
10ns      283.5mV    268.5mV    299mV
[Rising Waveform]
R_fixture= 50.000
V_fixture= 1.000
V_fixture_min= 0.970
V_fixture_max= 1.030
|time   V(typ)   V(min)   V(max)
0s        675.9mV    661mV      706.5mV
438ps     676.3mV    661mV      708.1mV
517ps     706.6mV    667mV      766.1mV
559ps     748.3mV    692mV      841mV
595ps     808.7mV    727.5mV    907mV
661ps     910.1mV    830.2mV    973.7mV
711ps     949.4mV    890.1mV    998.4mV
763ps     971.8mV    925.1mV    1.012V
922ps     995mV      961.8mV    1.027V
10ns      1V         970mV      1.03V
[Falling Waveform]
R_fixture= 50.000
V_fixture= 1.000
V_fixture_min= 0.970
V_fixture_max= 1.030
|time   V(typ)   V(min)   V(max)
0s        1V         970mV      1.03V
453ps     1.002V     970.2mV    1.032V
493ps     999.7mV    971.6mV    1.003V
524ps     976.6mV    969.3mV    946.8mV
558ps     923.4mV    948.4mV    877.9mV
599ps     847.4mV    894.3mV    815.4mV
649ps     777mV      818.6mV    769.2mV
760ps     707.8mV    715.9mV    725.8mV
931ps     682.4mV    673.2mV    710.2mV
10ns      675.9mV    661mV      706.5mV
[Falling Waveform]
R_fixture= 50.000
V_fixture= 0.0
V_fixture_min= 0.0
V_fixture_max= 0.0
|time   V(typ)   V(min)   V(max)
0s        283.5mV    268.5mV    299mV
439ps     284.8mV    269.3mV    300.2mV
483ps     282.1mV    269.5mV    269mV
510ps     262.2mV    267.6mV    215.8mV
543ps     209mV      249.8mV    148mV
621ps     84.89mV    142.6mV    55.82mV
671ps     45.85mV    81.61mV    30.71mV
721ps     25.33mV    44.93mV    17.2mV
881ps     4.306mV    7.5mV      3.007mV
10ns      1.756uV    11.98uV    783.8nV
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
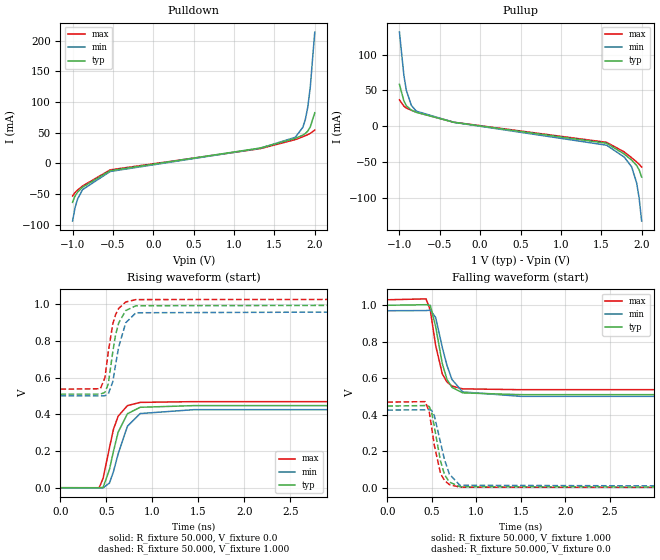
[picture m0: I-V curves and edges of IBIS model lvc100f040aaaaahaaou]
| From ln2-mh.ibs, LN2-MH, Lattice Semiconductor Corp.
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|   Model lvc100f040aaaaahaaou
[Model] lvc100f040aaaaahaaou
Model_type Output
Polarity   Non-Inverting
Enable   Active-High
Vmeas =  0.500V
Cref =  0.0F
Rref =  1.000M
Vref =  0.0V
C_comp   2.000pF   1.500pF   2.500pF
[Temperature Range]   25.000   0.125k   -40.000
[Voltage Range]   1.000V   0.970V   1.030V
[C Comp Corner]
C_comp   2.000pF   1.500pF   2.500pF
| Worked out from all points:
|   slope of the pulldown table from 0 to 0.15 V, typ, clamps not added: 51.9 ohm
|   slope of the pullup table from 0 to 0.15 V, typ, clamps not added: 59.8 ohm
|   rising waveform, R_fixture 50.000, V_fixture 0.0: 20-80 % time 141ps typ, 160ps min, 130ps max; typ from 0 V to 0.448 V
|   rising waveform, R_fixture 50.000, V_fixture 1.000: 20-80 % time 100ps typ, 114ps min, 95.5ps max; typ from 0.51 V to 1 V
|   falling waveform, R_fixture 50.000, V_fixture 1.000: 20-80 % time 122ps typ, 154ps min, 112ps max; typ from 1 V to 0.51 V
|   falling waveform, R_fixture 50.000, V_fixture 0.0: 20-80 % time 110ps typ, 132ps min, 102ps max; typ from 0.448 V to 0 V
[Pulldown]
|Voltage   I(typ)   I(min)   I(max)
-1V       -63.47mA   -93.98mA   -53.11mA
-969mV    -53.15mA   -72.21mA   -47.49mA
-938mV    -46.86mA   -58.19mA   -43.5mA
-876mV    -38.86mA   -42.87mA   -36.92mA
-535mV    -11.96mA   -13.26mA   -10.63mA
1.325V    24.99mA    24.63mA    23.97mA
1.759V    40.71mA    42.52mA    38.75mA
1.852V    46.03mA    58.67mA    43.45mA
1.883V    48.67mA    71.37mA    45.1mA
1.914V    52.67mA    92.1mA     46.87mA
1.945V    59.58mA    125.2mA    48.96mA
2V        82.55mA    214.1mA    54.18mA
[Pullup]
|Voltage   I(typ)   I(min)   I(max)
-1V       58.56mA    131.5mA    36.79mA
-945mV    35.34mA    71.08mA    28.02mA
-914mV    28.53mA    49.77mA    25.41mA
-852mV    22.42mA    28.99mA    22.27mA
-790mV    19.35mA    20.98mA    19.73mA
-325mV    5.467mA    5.464mA    5.583mA
1.566V    -23.77mA   -26.5mA    -22.47mA
1.783V    -38.74mA   -42.91mA   -35.79mA
1.876V    -47.2mA    -56.67mA   -43.95mA
1.938V    -54.8mA    -79.02mA   -49.84mA
1.969V    -60.88mA   -100.2mA   -53.08mA
2V        -70.96mA   -132.3mA   -56.91mA
[Ramp]
| variable   typ   min   max
dV/dt_r   0.269/0.141n   0.256/0.160n   0.282/0.130n
dV/dt_f   0.294/0.123n   0.281/0.155n   0.295/0.112n
R_load = 50.000
[Rising Waveform]
R_fixture= 50.000
V_fixture= 0.0
V_fixture_min= 0.0
V_fixture_max= 0.0
|time   V(typ)   V(min)   V(max)
0s        1.278uV    8.889uV    563.5nV
421ps     -461.1uV   -257.6uV   -93.3uV
464ps     1.809mV    -672.2uV   51.57mV
533ps     99.44mV    25.46mV    217.8mV
577ps     199.6mV    88.71mV    319.2mV
628ps     303.4mV    185.3mV    390.8mV
729ps     403.7mV    335.9mV    447.7mV
867ps     438.7mV    404.5mV    465.4mV
1.449ns   447.7mV    425.7mV    469.5mV
10ns      447.8mV    425.9mV    469.5mV
[Rising Waveform]
R_fixture= 50.000
V_fixture= 1.000
V_fixture_min= 0.970
V_fixture_max= 1.030
|time   V(typ)   V(min)   V(max)
0s        510.4mV    500.9mV    537.6mV
434ps     510.6mV    500.6mV    539.7mV
484ps     520.2mV    501.9mV    600.1mV
520ps     565.5mV    510.9mV    740mV
569ps     739.8mV    577.4mV    892.5mV
599ps     832mV      669mV      942.9mV
633ps     897.9mV    767.2mV    977.5mV
710ps     966.2mV    899.5mV    1.013V
821ps     992.5mV    954.2mV    1.026V
10ns      1V         970mV      1.03V
[Falling Waveform]
R_fixture= 50.000
V_fixture= 1.000
V_fixture_min= 0.970
V_fixture_max= 1.030
|time   V(typ)   V(min)   V(max)
0s        1V         970mV      1.03V
435ps     1.003V     970.9mV    1.035V
483ps     999.4mV    973.1mV    972.4mV
543ps     883.3mV    933.2mV    780.2mV
618ps     679.6mV    768.3mV    623.9mV
671ps     593.5mV    669.3mV    579.2mV
727ps     550.4mV    593mV      557.4mV
847ps     520.1mV    525.4mV    542.2mV
1.497ns   510.4mV    501.1mV    537.6mV
10ns      510.4mV    500.9mV    537.6mV
[Falling Waveform]
R_fixture= 50.000
V_fixture= 0.0
V_fixture_min= 0.0
V_fixture_max= 0.0
|time   V(typ)   V(min)   V(max)
0s        447.8mV    425.9mV    469.5mV
426ps     450.6mV    427.4mV    472.1mV
471ps     445.6mV    428.4mV    416.9mV
498ps     413.5mV    424mV      330.8mV
527ps     338.2mV    397.6mV    235.9mV
598ps     145.9mV    247.2mV    78.83mV
643ps     72.61mV    153.6mV    39.53mV
697ps     31.83mV    75.51mV    17.94mV
815ps     6.253mV    14.09mV    3.67mV
10ns      1.294uV    8.914uV    586.2nV
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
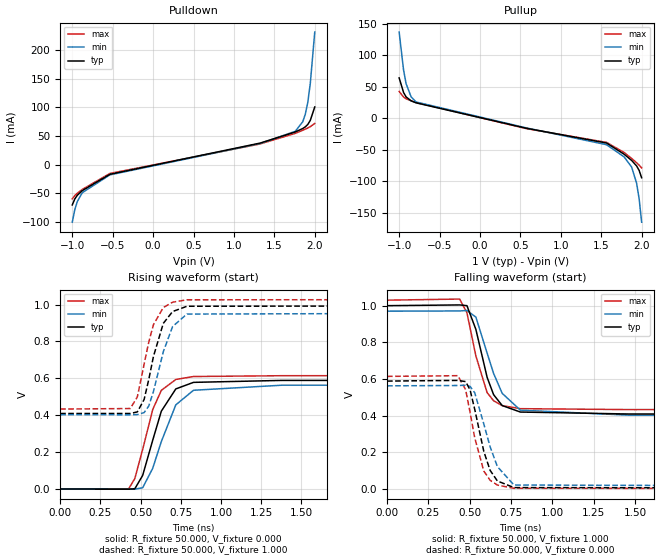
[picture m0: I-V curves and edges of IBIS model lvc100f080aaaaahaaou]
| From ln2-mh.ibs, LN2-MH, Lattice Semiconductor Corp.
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|   Model lvc100f080aaaaahaaou
[Model] lvc100f080aaaaahaaou
Model_type Output
Polarity   Non-Inverting
Enable   Active-High
Vmeas =  0.500V
Cref =  0.0F
Rref =  1.000M
Vref =  0.0V
C_comp   2.000pF   1.500pF   2.500pF
[Temperature Range]   25.000   0.125k   -40.000
[Voltage Range]   1.000V   0.970V   1.030V
[C Comp Corner]
C_comp   2.000pF   1.500pF   2.500pF
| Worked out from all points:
|   slope of the pulldown table from 0 to 0.15 V, typ, clamps not added: 34.6 ohm
|   slope of the pullup table from 0 to 0.15 V, typ, clamps not added: 34.6 ohm
|   rising waveform, R_fixture 50.000, V_fixture 0.000: 20-80 % time 124ps typ, 139ps min, 114ps max; typ from 0 V to 0.589 V
|   rising waveform, R_fixture 50.000, V_fixture 1.000: 20-80 % time 97.6ps typ, 108ps min, 92.8ps max; typ from 0.41 V to 1 V
|   falling waveform, R_fixture 50.000, V_fixture 1.000: 20-80 % time 103ps typ, 130ps min, 94.5ps max; typ from 1 V to 0.41 V
|   falling waveform, R_fixture 50.000, V_fixture 0.000: 20-80 % time 94.3ps typ, 115ps min, 87.1ps max; typ from 0.589 V to 0 V
[Pulldown]
|Voltage   I(typ)   I(min)   I(max)
-1V       -70.31mA   -100.4mA   -59.76mA
-969mV    -59.91mA   -78.59mA   -54.07mA
-938mV    -53.53mA   -64.49mA   -49.99mA
-876mV    -45.35mA   -48.99mA   -43.24mA
-535mV    -16.94mA   -17.96mA   -15.47mA
1.325V    37.47mA    36.7mA     35.97mA
1.759V    56.83mA    57.97mA    54.4mA
1.852V    62.86mA    74.74mA    59.84mA
1.883V    65.73mA    87.61mA    61.74mA
1.914V    69.96mA    108.5mA    63.75mA
1.945V    77.07mA    141.7mA    66.07mA
2V        100.4mA    230.9mA    71.7mA
[Pullup]
|Voltage   I(typ)   I(min)   I(max)
-1V       63.81mA    136.5mA    42.26mA
-945mV    40.49mA    75.99mA    33.39mA
-914mV    33.63mA    54.61mA    30.72mA
-852mV    27.39mA    33.7mA     27.46mA
-790mV    24.18mA    25.55mA    24.79mA
574mV     -16.16mA   -15.58mA   -16.71mA
1.566V    -39.55mA   -42.23mA   -38.53mA
1.783V    -57.29mA   -61.54mA   -54.52mA
1.876V    -67.13mA   -77.52mA   -64.03mA
1.938V    -75.95mA   -103.4mA   -70.86mA
1.969V    -82.99mA   -127.9mA   -74.61mA
2V        -94.66mA   -165.2mA   -79.05mA
[Ramp]
| variable   typ   min   max
dV/dt_r   0.353/0.124n   0.338/0.139n   0.369/0.114n
dV/dt_f   0.354/0.103n   0.340/0.131n   0.358/94.528p
R_load = 50.000
[Rising Waveform]
R_fixture = 50.000
V_fixture = 0.000
V_fixture_min = 0.000
V_fixture_max = 0.000
|  time   V(typ)   V(min)   V(max)
0s        1.385uV    7.816uV    610.1nV
426ps     -691.7uV   -391.1uV   1.14mV
464ps     1.092mV    -833.1uV   56.27mV
513ps     73.83mV    6.945mV    215.1mV
575ps     263.3mV    111.5mV    430.1mV
629ps     422.2mV    257.4mV    535.1mV
719ps     542.8mV    456.4mV    594.1mV
829ps     578.3mV    535.5mV    610mV
1.379ns   588.9mV    562.9mV    614.4mV
10ns      589mV      563.1mV    614.5mV
[Rising Waveform]
R_fixture = 50.000
V_fixture = 1.000
V_fixture_min = 0.970
V_fixture_max = 1.030
|  time   V(typ)   V(min)   V(max)
0s        409.5mV    402.9mV    433.5mV
436ps     409.5mV    402.5mV    436.4mV
480ps     418.2mV    403.5mV    500.1mV
522ps     485.6mV    414.5mV    676.9mV
551ps     594.5mV    450.4mV    797.9mV
580ps     718.9mV    528.7mV    891mV
641ps     898mV      743.7mV    983.8mV
699ps     962.3mV    881.2mV    1.013V
788ps     991mV      948.7mV    1.026V
10ns      1V         970mV      1.03V
[Falling Waveform]
R_fixture = 50.000
V_fixture = 1.000
V_fixture_min = 0.970
V_fixture_max = 1.030
|  time   V(typ)   V(min)   V(max)
0s        1V         970mV      1.03V
439ps     1.004V     971.2mV    1.036V
483ps     1V         973.9mV    961.3mV
537ps     870.6mV    937.5mV    725.9mV
605ps     609.4mV    741.4mV    526mV
644ps     515.1mV    630.9mV    482mV
696ps     455.7mV    522.2mV    455.4mV
806ps     420.3mV    430.6mV    438.7mV
1.464ns   409.6mV    403.1mV    433.6mV
10ns      409.5mV    402.9mV    433.5mV
[Falling Waveform]
R_fixture = 50.000
V_fixture = 0.000
V_fixture_min = 0.000
V_fixture_max = 0.000
|  time   V(typ)   V(min)   V(max)
0s        589mV      563.1mV    614.5mV
428ps     592.7mV    565mV      618.5mV
475ps     586.2mV    566.4mV    542.8mV
502ps     541.1mV    560.1mV    417.8mV
530ps     435.2mV    525.2mV    279.8mV
585ps     205.4mV    354.9mV    98.8mV
623ps     102.7mV    231mV      48.39mV
667ps     44.6mV     123mV      22.24mV
767ps     8.537mV    22.53mV    4.703mV
10ns      1.385uV    7.816uV    610.1nV
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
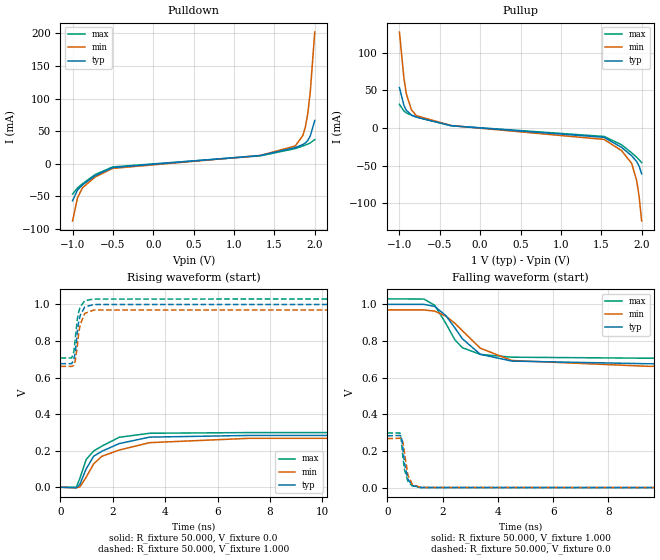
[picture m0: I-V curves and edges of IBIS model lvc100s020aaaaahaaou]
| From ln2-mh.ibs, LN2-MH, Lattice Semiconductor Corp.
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|   Model lvc100s020aaaaahaaou
[Model] lvc100s020aaaaahaaou
Model_type Output
Polarity   Non-Inverting
Enable   Active-High
Vmeas =  0.500V
Cref =  0.0F
Rref =  1.000M
Vref =  0.0V
C_comp   2.000pF   1.500pF   2.500pF
[Temperature Range]   25.000   0.125k   -40.000
[Voltage Range]   1.000V   0.970V   1.030V
[C Comp Corner]
C_comp   2.000pF   1.500pF   2.500pF
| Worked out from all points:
|   slope of the pulldown table from 0 to 0.15 V, typ, clamps not added: 104 ohm
|   slope of the pullup table from 0 to 0.15 V, typ, clamps not added: 119 ohm
|   rising waveform, R_fixture 50.000, V_fixture 0.0: 20-80 % time 1.18ns typ, 1.53ns min, 976ps max; typ from 0 V to 0.284 V
|   rising waveform, R_fixture 50.000, V_fixture 1.000: 20-80 % time 173ps typ, 179ps min, 166ps max; typ from 0.676 V to 1 V
|   falling waveform, R_fixture 50.000, V_fixture 1.000: 20-80 % time 1.06ns typ, 1.45ns min, 795ps max; typ from 1 V to 0.676 V
|   falling waveform, R_fixture 50.000, V_fixture 0.0: 20-80 % time 166ps typ, 176ps min, 162ps max; typ from 0.284 V to 0 V
[Pulldown]
|Voltage   I(typ)   I(min)   I(max)
-1V       -56.9mA    -88.01mA   -46.61mA
-938mV    -40.3mA    -52.1mA    -37.09mA
-876mV    -32.45mA   -36.85mA   -30.67mA
-721mV    -18.52mA   -20.39mA   -16.72mA
-504mV    -5.926mA   -7.266mA   -5.026mA
1.325V    12.55mA    12.61mA    12.01mA
1.759V    24.71mA    27.24mA    23.2mA
1.852V    29.35mA    43.19mA    27.18mA
1.883V    31.81mA    56.1mA     28.59mA
1.914V    35.72mA    77.31mA    30.13mA
1.945V    42.7mA     111.2mA    32mA
2V        66.34mA    202.1mA    36.97mA
[Pullup]
|Voltage   I(typ)   I(min)   I(max)
-1V       53.78mA    127.5mA    31.52mA
-945mV    30.36mA    66.68mA    22.72mA
-914mV    23.53mA    45.23mA    20.14mA
-852mV    17.48mA    24.38mA    17.1mA
-790mV    14.53mA    16.45mA    14.69mA
-356mV    3.112mA    3.321mA    3.089mA
1.535V    -12.25mA   -15.03mA   -11.05mA
1.752V    -25.62mA   -29.91mA   -22.18mA
1.876V    -36.63mA   -46.72mA   -32.81mA
1.938V    -44.29mA   -69.36mA   -38.7mA
1.969V    -50.45mA   -90.81mA   -41.95mA
2V        -60.71mA   -123.3mA   -45.82mA
[Ramp]
| variable   typ   min   max
dV/dt_r   0.170/1.180n   0.161/1.531n   0.179/0.979n
dV/dt_f   0.194/1.069n   0.185/1.470n   0.194/0.798n
R_load = 50.000
[Rising Waveform]
R_fixture= 50.000
V_fixture= 0.0
V_fixture_min= 0.0
V_fixture_max= 0.0
|time   V(typ)   V(min)   V(max)
0s        1.742uV    11.95uV    763.4nV
604ps     -3.105mV   -2.768mV   1.002mV
739ps     15.62mV    1.746mV    47.38mV
984ps     100.8mV    55.56mV    152.3mV
1.269ns   169.8mV    128mV      198.3mV
1.582ns   196.9mV    169.4mV    224.8mV
2.242ns   238.8mV    203.4mV    273.3mV
3.403ns   274.1mV    243.9mV    295.4mV
7.212ns   283.4mV    267.7mV    299mV
50ns      283.5mV    268.4mV    299mV
[Rising Waveform]
R_fixture= 50.000
V_fixture= 1.000
V_fixture_min= 0.970
V_fixture_max= 1.030
|time   V(typ)   V(min)   V(max)
0s        675.9mV    661mV      706.5mV
431ps     675.9mV    661mV      707.2mV
513ps     700.4mV    665.9mV    741mV
568ps     736mV      692.8mV    815.9mV
640ps     843.8mV    766.9mV    914.9mV
692ps     899.4mV    836.8mV    955.9mV
753ps     939.5mV    889.6mV    985.6mV
930ps     985.9mV    950.8mV    1.02V
1.272ns   999.2mV    968.9mV    1.029V
50ns      1V         970mV      1.03V
[Falling Waveform]
R_fixture= 50.000
V_fixture= 1.000
V_fixture_min= 0.970
V_fixture_max= 1.030
|time   V(typ)   V(min)   V(max)
0s        1V         970mV      1.03V
1.324ns   1V         969.8mV    1.029V
1.714ns   989.1mV    963.1mV    994.9mV
2.114ns   939.1mV    936.3mV    896.8mV
2.443ns   872.2mV    897mV      807.4mV
2.715ns   812.6mV    856.4mV    763.7mV
3.365ns   727.7mV    761mV      727.5mV
4.504ns   690.9mV    694.1mV    712.1mV
9.433ns   676.3mV    662.4mV    706.5mV
50ns      675.9mV    661mV      706.5mV
[Falling Waveform]
R_fixture= 50.000
V_fixture= 0.0
V_fixture_min= 0.0
V_fixture_max= 0.0
|time   V(typ)   V(min)   V(max)
0s        283.5mV    268.4mV    299mV
455ps     285.3mV    270.3mV    298.9mV
491ps     282.6mV    270mV      278.3mV
528ps     260.9mV    266.9mV    225.3mV
573ps     201.7mV    243.1mV    153.2mV
623ps     132.6mV    187.6mV    98.72mV
744ps     47.33mV    70.37mV    35.64mV
905ps     12.98mV    19mV       9.915mV
1.205ns   1.745mV    2.251mV    1.519mV
50ns      1.75uV     11.98uV    772.4nV
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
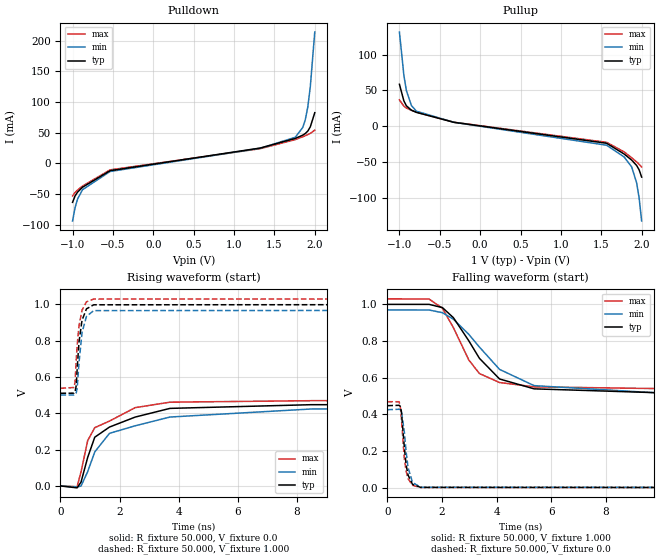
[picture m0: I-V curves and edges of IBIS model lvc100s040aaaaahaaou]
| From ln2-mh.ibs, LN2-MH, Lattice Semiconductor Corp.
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|   Model lvc100s040aaaaahaaou
[Model] lvc100s040aaaaahaaou
Model_type Output
Polarity   Non-Inverting
Enable   Active-High
Vmeas =  0.500V
Cref =  0.0F
Rref =  1.000M
Vref =  0.0V
C_comp   2.000pF   1.500pF   2.500pF
[Temperature Range]   25.000   0.125k   -40.000
[Voltage Range]   1.000V   0.970V   1.030V
[C Comp Corner]
C_comp   2.000pF   1.500pF   2.500pF
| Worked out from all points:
|   slope of the pulldown table from 0 to 0.15 V, typ, clamps not added: 51.9 ohm
|   slope of the pullup table from 0 to 0.15 V, typ, clamps not added: 59.8 ohm
|   rising waveform, R_fixture 50.000, V_fixture 0.0: 20-80 % time 1.41ns typ, 1.81ns min, 1.14ns max; typ from 0 V to 0.448 V
|   rising waveform, R_fixture 50.000, V_fixture 1.000: 20-80 % time 163ps typ, 172ps min, 160ps max; typ from 0.51 V to 1 V
|   falling waveform, R_fixture 50.000, V_fixture 1.000: 20-80 % time 1.4ns typ, 1.89ns min, 1.06ns max; typ from 1 V to 0.51 V
|   falling waveform, R_fixture 50.000, V_fixture 0.0: 20-80 % time 175ps typ, 191ps min, 168ps max; typ from 0.448 V to 0 V
[Pulldown]
|Voltage   I(typ)   I(min)   I(max)
-1V       -63.47mA   -93.98mA   -53.11mA
-969mV    -53.15mA   -72.21mA   -47.49mA
-938mV    -46.86mA   -58.19mA   -43.5mA
-876mV    -38.86mA   -42.87mA   -36.92mA
-535mV    -11.96mA   -13.26mA   -10.63mA
1.325V    24.99mA    24.63mA    23.97mA
1.759V    40.71mA    42.52mA    38.75mA
1.852V    46.03mA    58.67mA    43.45mA
1.883V    48.67mA    71.36mA    45.1mA
1.914V    52.67mA    92.1mA     46.87mA
1.945V    59.58mA    125.2mA    48.96mA
2V        82.55mA    214.1mA    54.18mA
[Pullup]
|Voltage   I(typ)   I(min)   I(max)
-1V       58.56mA    131.5mA    36.79mA
-945mV    35.34mA    71.08mA    28.02mA
-914mV    28.53mA    49.77mA    25.41mA
-852mV    22.42mA    28.99mA    22.27mA
-790mV    19.35mA    20.98mA    19.73mA
-325mV    5.467mA    5.464mA    5.583mA
1.566V    -23.77mA   -26.5mA    -22.47mA
1.783V    -38.74mA   -42.91mA   -35.79mA
1.876V    -47.2mA    -56.67mA   -43.95mA
1.938V    -54.8mA    -79.02mA   -49.84mA
1.969V    -60.88mA   -100.2mA   -53.08mA
2V        -70.96mA   -132.3mA   -56.91mA
[Ramp]
| variable   typ   min   max
dV/dt_r   0.269/1.407n   0.256/1.804n   0.282/1.137n
dV/dt_f   0.294/1.401n   0.281/1.908n   0.295/1.064n
R_load = 50.000
[Rising Waveform]
R_fixture= 50.000
V_fixture= 0.0
V_fixture_min= 0.0
V_fixture_max= 0.0
|time   V(typ)   V(min)   V(max)
0s        1.278uV    8.889uV    563.5nV
563ps     -10.36mV   -5.539mV   -4.126mV
696ps     21.04mV    -727.4uV   76.72mV
921ps     156.8mV    78.66mV    249.5mV
1.161ns   268.4mV    187.4mV    321mV
1.66ns    324.4mV    289.8mV    357.4mV
2.53ns    379.3mV    331.3mV    431.2mV
3.706ns   427.1mV    379.5mV    461.3mV
8.501ns   447.5mV    423.9mV    469.5mV
50ns      447.8mV    425.9mV    469.5mV
[Rising Waveform]
R_fixture= 50.000
V_fixture= 1.000
V_fixture_min= 0.970
V_fixture_max= 1.030
|time   V(typ)   V(min)   V(max)
0s        510.4mV    500.9mV    537.6mV
458ps     510.9mV    500.6mV    542.1mV
494ps     517mV      502.6mV    572.6mV
534ps     553.8mV    511.5mV    691.8mV
568ps     651.1mV    542.4mV    779.4mV
628ps     792.3mV    677.6mV    881.2mV
730ps     912.5mV    844.9mV    967.6mV
881ps     975.1mV    933.8mV    1.014V
1.127ns   997.4mV    965.3mV    1.029V
50ns      1V         970mV      1.03V
[Falling Waveform]
R_fixture= 50.000
V_fixture= 1.000
V_fixture_min= 0.970
V_fixture_max= 1.030
|time   V(typ)   V(min)   V(max)
0s        1V         970mV      1.03V
1.529ns   1V         969.3mV    1.029V
2.018ns   982.3mV    954.6mV    978.7mV
2.419ns   927.4mV    919.1mV    872.9mV
2.983ns   801.3mV    836.6mV    696.8mV
3.372ns   705.8mV    767.1mV    622.9mV
4.108ns   593.3mV    645.6mV    574.2mV
5.372ns   539.6mV    557.1mV    550.4mV
11.39ns   511.4mV    504.4mV    537.8mV
50ns      510.4mV    500.9mV    537.6mV
[Falling Waveform]
R_fixture= 50.000
V_fixture= 0.0
V_fixture_min= 0.0
V_fixture_max= 0.0
|time   V(typ)   V(min)   V(max)
0s        447.8mV    425.9mV    469.5mV
430ps     449.9mV    428.3mV    469.4mV
472ps     445.2mV    427.4mV    446.6mV
514ps     416.4mV    421.3mV    381.3mV
624ps     219mV      302.4mV    157mV
689ps     125.1mV    196.1mV    90.25mV
758ps     70.11mV    111.5mV    50.81mV
924ps     18.47mV    28.93mV    13.59mV
1.219ns   2.554mV    3.505mV    2.167mV
50ns      1.284uV    8.911uV    571.9nV
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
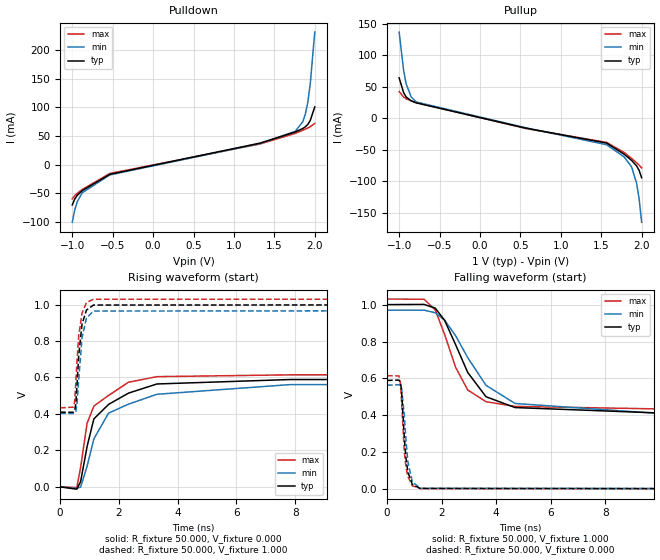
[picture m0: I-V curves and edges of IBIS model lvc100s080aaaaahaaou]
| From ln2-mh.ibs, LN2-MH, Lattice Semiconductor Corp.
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|   Model lvc100s080aaaaahaaou
[Model] lvc100s080aaaaahaaou
Model_type Output
Polarity   Non-Inverting
Enable   Active-High
Vmeas =  0.500V
Cref =  0.0F
Rref =  1.000M
Vref =  0.0V
C_comp   2.000pF   1.500pF   2.500pF
[Temperature Range]   25.000   0.125k   -40.000
[Voltage Range]   1.000V   0.970V   1.030V
[C Comp Corner]
C_comp   2.000pF   1.500pF   2.500pF
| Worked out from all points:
|   slope of the pulldown table from 0 to 0.15 V, typ, clamps not added: 34.6 ohm
|   slope of the pullup table from 0 to 0.15 V, typ, clamps not added: 34.6 ohm
|   rising waveform, R_fixture 50.000, V_fixture 0.000: 20-80 % time 1.06ns typ, 1.36ns min, 863ps max; typ from 0 V to 0.589 V
|   rising waveform, R_fixture 50.000, V_fixture 1.000: 20-80 % time 171ps typ, 178ps min, 167ps max; typ from 0.41 V to 1 V
|   falling waveform, R_fixture 50.000, V_fixture 1.000: 20-80 % time 1.21ns typ, 1.56ns min, 938ps max; typ from 1 V to 0.41 V
|   falling waveform, R_fixture 50.000, V_fixture 0.000: 20-80 % time 172ps typ, 188ps min, 165ps max; typ from 0.589 V to 0 V
[Pulldown]
|Voltage   I(typ)   I(min)   I(max)
-1V       -70.31mA   -100.4mA   -59.76mA
-969mV    -59.91mA   -78.59mA   -54.07mA
-938mV    -53.53mA   -64.49mA   -49.99mA
-876mV    -45.35mA   -48.99mA   -43.24mA
-535mV    -16.94mA   -17.96mA   -15.47mA
1.325V    37.47mA    36.7mA     35.97mA
1.759V    56.83mA    57.97mA    54.4mA
1.852V    62.86mA    74.73mA    59.84mA
1.883V    65.73mA    87.61mA    61.74mA
1.914V    69.96mA    108.5mA    63.75mA
1.945V    77.07mA    141.7mA    66.07mA
2V        100.4mA    230.9mA    71.7mA
[Pullup]
|Voltage   I(typ)   I(min)   I(max)
-1V       63.81mA    136.5mA    42.26mA
-945mV    40.49mA    75.98mA    33.39mA
-914mV    33.63mA    54.61mA    30.72mA
-852mV    27.39mA    33.7mA     27.46mA
-790mV    24.18mA    25.55mA    24.79mA
574mV     -16.16mA   -15.58mA   -16.71mA
1.566V    -39.55mA   -42.23mA   -38.53mA
1.783V    -57.29mA   -61.54mA   -54.52mA
1.876V    -67.13mA   -77.52mA   -64.03mA
1.938V    -75.95mA   -103.4mA   -70.86mA
1.969V    -82.99mA   -127.9mA   -74.61mA
2V        -94.66mA   -165.2mA   -79.05mA
[Ramp]
| variable   typ   min   max
dV/dt_r   0.353/1.056n   0.338/1.355n   0.369/0.862n
dV/dt_f   0.354/1.209n   0.340/1.565n   0.358/0.942n
R_load = 50.000
[Rising Waveform]
R_fixture = 50.000
V_fixture = 0.000
V_fixture_min = 0.000
V_fixture_max = 0.000
|  time   V(typ)   V(min)   V(max)
0s        1.912uV    8.351uV    610.1nV
567ps     -12.56mV   -7.636mV   -3.789mV
696ps     28.76mV    -1.61mV    106.9mV
917ps     221.2mV    113.3mV    348.7mV
1.147ns   372.7mV    263.2mV    443.1mV
1.65ns    452.5mV    404.8mV    501.7mV
2.327ns   514.2mV    453.7mV    574mV
3.297ns   564.4mV    507.9mV    604.5mV
7.818ns   588.7mV    560.8mV    614.4mV
50ns      589mV      563.1mV    614.5mV
[Rising Waveform]
R_fixture = 50.000
V_fixture = 1.000
V_fixture_min = 0.970
V_fixture_max = 1.030
|  time   V(typ)   V(min)   V(max)
0s        409.5mV    402.9mV    433.5mV
453ps     409.3mV    402.2mV    437.1mV
494ps     418.9mV    404.1mV    469.6mV
534ps     456.2mV    414.1mV    574.2mV
572ps     553.3mV    452mV      688.7mV
633ps     721.9mV    590mV      829.1mV
745ps     892.5mV    818.2mV    952.9mV
895ps     969.5mV    925.9mV    1.011V
1.135ns   997.2mV    964.3mV    1.029V
50ns      1V         970mV      1.03V
[Falling Waveform]
R_fixture = 50.000
V_fixture = 1.000
V_fixture_min = 0.970
V_fixture_max = 1.030
|  time   V(typ)   V(min)   V(max)
0s        1V         970mV      1.03V
1.358ns   1.001V     969.9mV    1.029V
1.768ns   980.7mV    955.9mV    971mV
2.112ns   914.4mV    915.5mV    837.8mV
2.512ns   783.3mV    831.9mV    660.8mV
2.958ns   632.2mV    712.5mV    537.3mV
3.628ns   500.8mV    562.6mV    473.9mV
4.692ns   442.2mV    464.3mV    448.4mV
10.33ns   410.7mV    406.4mV    433.8mV
50ns      409.5mV    402.9mV    433.5mV
[Falling Waveform]
R_fixture = 50.000
V_fixture = 0.000
V_fixture_min = 0.000
V_fixture_max = 0.000
|  time   V(typ)   V(min)   V(max)
0s        589mV      563.1mV    614.5mV
435ps     591.3mV    566mV      613.6mV
487ps     580.9mV    563.6mV    577.2mV
527ps     542.5mV    553.4mV    492.3mV
632ps     286.5mV    403.6mV    204.8mV
693ps     169.2mV    267mV      121.7mV
762ps     94.75mV    151.1mV    68.52mV
928ps     25.03mV    39.11mV    18.49mV
1.222ns   3.711mV    4.895mV    3.256mV
50ns      1.912uV    8.351uV    610.1nV
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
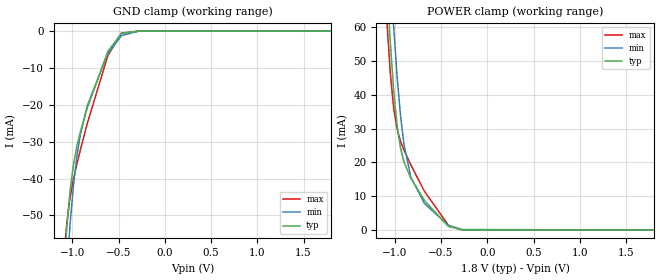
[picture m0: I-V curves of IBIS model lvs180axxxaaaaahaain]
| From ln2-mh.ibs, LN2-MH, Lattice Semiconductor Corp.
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|   Model lvs180axxxaaaaahaain
[Model] lvs180axxxaaaaahaain
Model_type Input
Polarity   Non-Inverting
Enable   Active-High
Vinl =  1.150V
Vinh =  1.350V
C_comp   2.000pF   1.500pF   2.500pF
[Temperature Range]   25.000   0.125k   -40.000
[Voltage Range]   1.800V   1.750V   1.850V
[C Comp Corner]
C_comp   2.000pF   1.500pF   2.500pF
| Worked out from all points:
|   GND clamp passes 1 mA (typ) near -0.49 V on its own axis
|   POWER clamp passes 1 mA (typ) near -0.42 V on its own axis
[GND_clamp]
|Voltage   I(typ)   I(min)   I(max)
-1.8V     -562.4mA   -568.2mA   -562.7mA
-1.097V   -67.19mA   -81.53mA   -63.16mA
-1.06V    -53.27mA   -65.4mA    -52.14mA
-1.023V   -43.04mA   -51.99mA   -44.96mA
-986mV    -36.01mA   -41.49mA   -39.96mA
-949mV    -31.06mA   -33.66mA   -35.87mA
-912mV    -27.21mA   -27.94mA   -32.13mA
-838mV    -20.81mA   -20.19mA   -25.03mA
-616mV    -5.535mA   -6.113mA   -6.675mA
-468mV    -585.4uA   -1.215mA   -547.8uA
-283mV    -3.281uA   -28.22uA   -915.4nA
1.8V      0A         0A         0A
[POWER_clamp]
|Voltage   I(typ)   I(min)   I(max)
-1.789V   606.3mA    621.4mA    600mA
-1.086V   73.69mA    97.33mA    62.02mA
-1.049V   55.55mA    77.46mA    46.39mA
-1.012V   41.07mA    59.94mA    35.89mA
-975mV    30.76mA    45.25mA    29.8mA
-938mV    24.18mA    33.73mA    26.21mA
-901mV    20.13mA    25.33mA    23.62mA
-827mV    15.31mA    15.65mA    19.27mA
-679mV    8.694mA    7.826mA    11.41mA
-420mV    1.032mA    1.329mA    1.377mA
-272mV    29.76uA    129.3uA    18.29uA
1.8V      0A         0A         0A
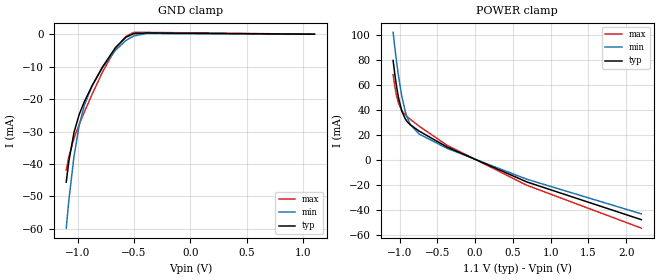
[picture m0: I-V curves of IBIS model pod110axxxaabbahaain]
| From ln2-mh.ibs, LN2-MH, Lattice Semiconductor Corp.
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|   Model pod110axxxaabbahaain
[Model] pod110axxxaabbahaain
Model_type Input
Polarity   Non-Inverting
Enable   Active-High
Vinl =  0.700V
Vinh =  0.900V
C_comp   2.000pF   1.500pF   2.500pF
[Temperature Range]   25.000   0.125k   -40.000
[Voltage Range]   1.100V   1.070V   1.130V
[C Comp Corner]
C_comp   2.000pF   1.500pF   2.500pF
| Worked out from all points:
|   GND clamp passes 1 mA (typ) near -0.57 V on its own axis
|   POWER clamp passes 1 mA (typ) near -0.04 V on its own axis
[GND_clamp]
|Voltage   I(typ)   I(min)   I(max)
-1.1V     -45.58mA   -59.75mA   -41.85mA
-1.077V   -39.17mA   -51.24mA   -37.74mA
-1.031V   -30.23mA   -37.56mA   -32.05mA
-985mV    -24.71mA   -28.11mA   -27.78mA
-939mV    -20.75mA   -21.86mA   -23.93mA
-870mV    -15.84mA   -15.82mA   -18.46mA
-778mV    -10.06mA   -10.24mA   -11.63mA
-663mV    -4.09mA    -4.916mA   -4.435mA
-571mV    -940.1uA   -1.916mA   -654.2uA
-502mV    189.8uA    -538.1uA   565.4uA
-387mV    386uA      205.4uA    562.5uA
1.1V      0A         0A         0A
[POWER_clamp]
|Voltage   I(typ)   I(min)   I(max)
-1.085V   79.38mA    101.9mA    68.05mA
-1.062V   68.19mA    89.63mA    58.49mA
-1.039V   58.44mA    78.27mA    50.98mA
-1.016V   50.29mA    67.93mA    45.5mA
-970mV    38.85mA    50.73mA    39.09mA
-924mV    32.55mA    38.45mA    35.72mA
-901mV    30.57mA    34.03mA    34.44mA
-855mV    27.76mA    27.86mA    32.15mA
-740mV    22.83mA    20.47mA    26.75mA
-372mV    10.1mA     9.018mA    11.51mA
686mV     -17.91mA   -15.74mA   -20.57mA
2.2V      -48.09mA   -43.45mA   -54.88mA
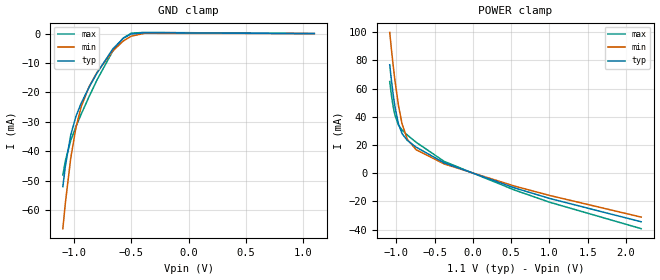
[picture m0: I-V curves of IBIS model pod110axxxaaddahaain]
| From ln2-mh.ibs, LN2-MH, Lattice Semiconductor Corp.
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|   Model pod110axxxaaddahaain
[Model] pod110axxxaaddahaain
Model_type Input
Polarity   Non-Inverting
Enable   Active-High
Vinl =  0.700V
Vinh =  0.900V
C_comp   2.000pF   1.500pF   2.500pF
[Temperature Range]   25.000   0.125k   -40.000
[Voltage Range]   1.100V   1.070V   1.130V
[C Comp Corner]
C_comp   2.000pF   1.500pF   2.500pF
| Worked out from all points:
|   GND clamp passes 1 mA (typ) near -0.55 V on its own axis
|   POWER clamp passes 1 mA (typ) near -0.05 V on its own axis
[GND_clamp]
|Voltage   I(typ)   I(min)   I(max)
-1.1V     -51.97mA   -66.23mA   -48mA
-1.077V   -44.75mA   -57.16mA   -43.03mA
-1.031V   -34.43mA   -42.31mA   -36.31mA
-985mV    -28.04mA   -31.8mA    -31.52mA
-939mV    -23.57mA   -24.77mA   -27.31mA
-870mV    -18.17mA   -17.99mA   -21.37mA
-801mV    -13.36mA   -13.2mA    -15.73mA
-663mV    -5.212mA   -5.904mA   -5.932mA
-571mV    -1.575mA   -2.509mA   -1.511mA
-502mV    -148.1uA   -891.8uA   127.5uA
-387mV    264.1uA    87.44uA    395.6uA
1.1V      0A         0A         0A
[POWER_clamp]
|Voltage   I(typ)   I(min)   I(max)
-1.085V   76.93mA    99.87mA    65.01mA
-1.062V   65.45mA    87.45mA    54.97mA
-1.039V   55.38mA    75.92mA    46.96mA
-1.016V   46.88mA    65.39mA    41.03mA
-970mV    34.81mA    47.75mA    34.08mA
-924mV    28.14mA    35.06mA    30.59mA
-855mV    23.24mA    24.07mA    27.09mA
-740mV    18.51mA    16.67mA    21.97mA
-372mV    7.313mA    6.582mA    8.346mA
548mV     -10.42mA   -9.152mA   -11.95mA
1.008V    -17.92mA   -15.8mA    -20.62mA
2.2V      -34.42mA   -31.1mA    -39.29mA
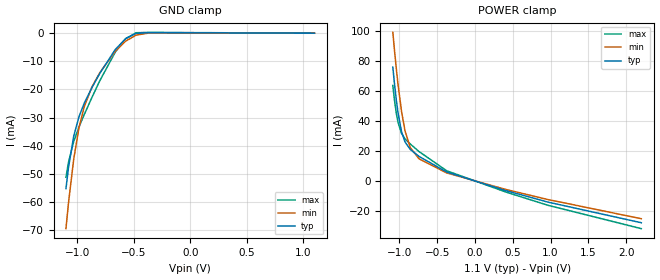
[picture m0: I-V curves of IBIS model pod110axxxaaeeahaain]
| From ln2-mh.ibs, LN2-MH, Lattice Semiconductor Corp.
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|   Model pod110axxxaaeeahaain
[Model] pod110axxxaaeeahaain
Model_type Input
Polarity   Non-Inverting
Enable   Active-High
Vinl =  0.700V
Vinh =  0.900V
C_comp   2.000pF   1.500pF   2.500pF
[Temperature Range]   25.000   0.125k   -40.000
[Voltage Range]   1.100V   1.070V   1.130V
[C Comp Corner]
C_comp   2.000pF   1.500pF   2.500pF
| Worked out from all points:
|   GND clamp passes 1 mA (typ) near -0.54 V on its own axis
|   POWER clamp passes 1 mA (typ) near -0.06 V on its own axis
[GND_clamp]
|Voltage   I(typ)   I(min)   I(max)
-1.1V     -55.25mA   -69.49mA   -51.21mA
-1.077V   -47.62mA   -60.15mA   -45.78mA
-1.031V   -36.59mA   -44.72mA   -38.47mA
-985mV    -29.73mA   -33.69mA   -33.39mA
-939mV    -25mA      -26.25mA   -29.01mA
-870mV    -19.35mA   -19.09mA   -22.83mA
-801mV    -14.33mA   -14.07mA   -16.96mA
-663mV    -5.792mA   -6.411mA   -6.703mA
-571mV    -1.909mA   -2.817mA   -1.962mA
-479mV    -63.68uA   -691.7uA   160.8uA
-364mV    190.5uA    70.67uA    282.1uA
1.1V      0A         0A         0A
[POWER_clamp]
|Voltage   I(typ)   I(min)   I(max)
-1.085V   75.77mA    98.91mA    63.59mA
-1.062V   64.16mA    86.42mA    53.34mA
-1.039V   53.94mA    74.8mA     45.09mA
-1.016V   45.28mA    64.18mA    38.94mA
-970mV    32.9mA     46.34mA    31.71mA
-924mV    26.04mA    33.44mA    28.14mA
-855mV    21.07mA    22.26mA    24.68mA
-740mV    16.43mA    14.83mA    19.68mA
-372mV    5.965mA    5.399mA    6.826mA
410mV     -6.377mA   -5.6mA     -7.318mA
962mV     -13.95mA   -12.26mA   -16.07mA
2.2V      -27.74mA   -25.06mA   -31.67mA
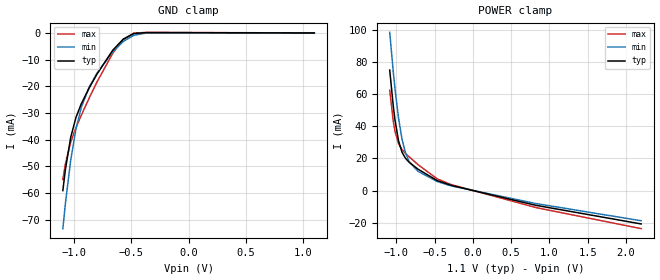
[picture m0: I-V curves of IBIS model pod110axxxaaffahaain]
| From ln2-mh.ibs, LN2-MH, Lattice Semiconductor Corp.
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|   Model pod110axxxaaffahaain
[Model] pod110axxxaaffahaain
Model_type Input
Polarity   Non-Inverting
Enable   Active-High
Vinl =  0.700V
Vinh =  0.900V
C_comp   2.000pF   1.500pF   2.500pF
[Temperature Range]   25.000   0.125k   -40.000
[Voltage Range]   1.100V   1.070V   1.130V
[C Comp Corner]
C_comp   2.000pF   1.500pF   2.500pF
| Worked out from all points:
|   GND clamp passes 1 mA (typ) near -0.53 V on its own axis
|   POWER clamp passes 1 mA (typ) near -0.09 V on its own axis
[GND_clamp]
|Voltage   I(typ)   I(min)   I(max)
-1.1V     -59.15mA   -73.43mA   -54.98mA
-1.077V   -51.04mA   -63.76mA   -48.98mA
-1.031V   -39.12mA   -47.64mA   -40.92mA
-985mV    -31.67mA   -35.94mA   -35.49mA
-939mV    -26.61mA   -27.98mA   -30.9mA
-870mV    -20.67mA   -20.35mA   -24.47mA
-801mV    -15.43mA   -15.05mA   -18.37mA
-663mV    -6.462mA   -7mA       -7.595mA
-571mV    -2.297mA   -3.178mA   -2.49mA
-479mV    -222.2uA   -868uA     -43.58uA
-364mV    137.5uA    17.75uA    209.1uA
1.1V      0A         0A         0A
[POWER_clamp]
|Voltage   I(typ)   I(min)   I(max)
-1.085V   74.85mA    98.25mA    62.33mA
-1.039V   52.63mA    73.92mA    43.23mA
-1.016V   43.75mA    63.17mA    36.78mA
-970mV    30.94mA    45.03mA    29.16mA
-924mV    23.81mA    31.84mA    25.47mA
-878mV    20.02mA    23.28mA    23.08mA
-832mV    17.65mA    18.11mA    21.03mA
-717mV    13.4mA     12.03mA    16.24mA
-464mV    6.212mA    5.676mA    7.298mA
-280mV    3.274mA    2.937mA    3.726mA
824mV     -9.095mA   -7.994mA   -10.47mA
2.2V      -20.67mA   -18.69mA   -23.59mA
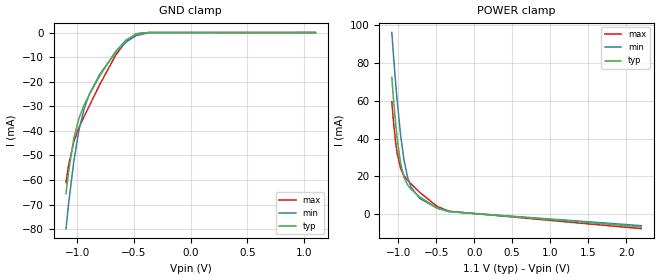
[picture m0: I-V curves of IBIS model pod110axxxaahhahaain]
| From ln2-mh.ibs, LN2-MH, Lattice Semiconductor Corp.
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|   Model pod110axxxaahhahaain
[Model] pod110axxxaahhahaain
Model_type Input
Polarity   Non-Inverting
Enable   Active-High
Vinl =  0.700V
Vinh =  0.900V
C_comp   2.000pF   1.500pF   2.500pF
[Temperature Range]   25.000   0.125k   -40.000
[Voltage Range]   1.100V   1.070V   1.130V
[C Comp Corner]
C_comp   2.000pF   1.500pF   2.500pF
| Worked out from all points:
|   GND clamp passes 1 mA (typ) near -0.50 V on its own axis
|   POWER clamp passes 1 mA (typ) near -0.26 V on its own axis
[GND_clamp]
|Voltage   I(typ)   I(min)   I(max)
-1.1V     -65.53mA   -79.82mA   -61.03mA
-1.077V   -56.58mA   -69.6mA    -53.91mA
-1.031V   -43.13mA   -52.33mA   -44.42mA
-985mV    -34.76mA   -39.57mA   -38.57mA
-939mV    -29.36mA   -30.86mA   -34.01mA
-893mV    -25.13mA   -24.97mA   -29.72mA
-801mV    -17.52mA   -16.9mA    -21.03mA
-663mV    -7.749mA   -8.116mA   -9.313mA
-571mV    -3.061mA   -3.87mA    -3.538mA
-479mV    -548.1uA   -1.213mA   -475.2uA
-364mV    31.32uA    -87.68uA   64.05uA
1.1V      0A         0A         0A
[POWER_clamp]
|Voltage   I(typ)   I(min)   I(max)
-1.085V   72.51mA    96.29mA    59.49mA
-1.062V   60.46mA    83.55mA    48.51mA
-1.039V   49.72mA    71.65mA    39.46mA
-1.016V   40.5mA     60.7mA     32.52mA
-970mV    27.02mA    42.14mA    24.22mA
-924mV    19.45mA    28.52mA    20.32mA
-878mV    15.49mA    19.62mA    17.95mA
-832mV    13.12mA    14.28mA    15.97mA
-717mV    9.094mA    8.23mA     11.47mA
-487mV    3.223mA    3.061mA    4.021mA
-326mV    1.306mA    1.272mA    1.476mA
2.2V      -6.792mA   -6.148mA   -7.741mA
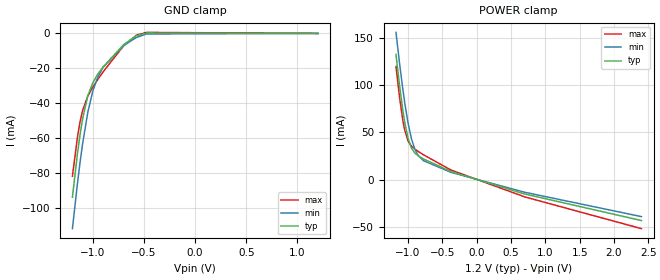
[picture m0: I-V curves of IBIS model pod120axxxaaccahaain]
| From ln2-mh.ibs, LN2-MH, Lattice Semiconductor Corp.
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|   Model pod120axxxaaccahaain
[Model] pod120axxxaaccahaain
Model_type Input
Polarity   Non-Inverting
Enable   Active-High
Vinl =  0.800V
Vinh =  1.000V
C_comp   2.000pF   1.500pF   2.500pF
[Temperature Range]   25.000   0.125k   -40.000
[Voltage Range]   1.200V   1.160V   1.240V
[C Comp Corner]
C_comp   2.000pF   1.500pF   2.500pF
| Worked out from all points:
|   GND clamp passes 1 mA (typ) near -0.56 V on its own axis
|   POWER clamp passes 1 mA (typ) near -0.04 V on its own axis
[GND_clamp]
|Voltage   I(typ)   I(min)   I(max)
-1.2V     -93.71mA   -111.7mA   -81.73mA
-1.15V    -68.33mA   -85.38mA   -58.86mA
-1.125V   -57.68mA   -73.59mA   -50.4mA
-1.1V     -48.67mA   -62.89mA   -44.02mA
-1.05V    -35.73mA   -45.23mA   -35.87mA
-1V       -28.1mA    -32.78mA   -30.61mA
-950mV    -23.14mA   -24.7mA    -26.17mA
-900mV    -19.2mA    -19.39mA   -21.99mA
-700mV    -6.444mA   -7.025mA   -7.106mA
-575mV    -1.323mA   -2.293mA   -1.037mA
-475mV    262uA      -321.4uA   594.8uA
1.2V      0A         0A         0A
[POWER_clamp]
|Voltage   I(typ)   I(min)   I(max)
-1.175V   132.4mA    155.7mA    119.6mA
-1.125V   100.6mA    124.1mA    88.02mA
-1.075V   73.05mA    95.42mA    62.45mA
-1.05V    61.43mA    82.45mA    52.92mA
-1V       43.71mA    60.04mA    40.89mA
-950mV    33.38mA    43.17mA    35.34mA
-900mV    28.08mA    32mA       32.23mA
-850mV    25.04mA    25.33mA    29.74mA
-775mV    21.78mA    20mA       26.24mA
-375mV    8.527mA    7.673mA    10.1mA
700mV     -15.24mA   -13.41mA   -18.3mA
2.4V      -43.34mA   -39.18mA   -51.91mA
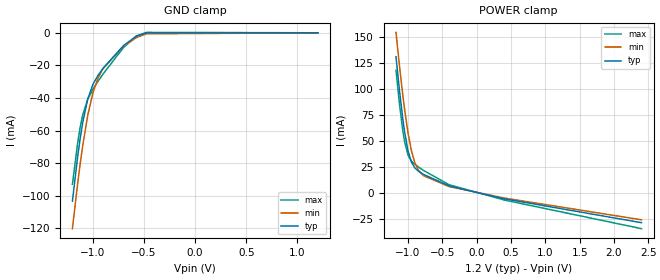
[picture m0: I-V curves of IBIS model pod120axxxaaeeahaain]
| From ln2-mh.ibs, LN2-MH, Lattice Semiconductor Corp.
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|   Model pod120axxxaaeeahaain
[Model] pod120axxxaaeeahaain
Model_type Input
Polarity   Non-Inverting
Enable   Active-High
Vinl =  0.800V
Vinh =  1.000V
C_comp   2.000pF   1.500pF   2.500pF
[Temperature Range]   25.000   0.125k   -40.000
[Voltage Range]   1.200V   1.160V   1.240V
[C Comp Corner]
C_comp   2.000pF   1.500pF   2.500pF
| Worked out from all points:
|   GND clamp passes 1 mA (typ) near -0.54 V on its own axis
|   POWER clamp passes 1 mA (typ) near -0.07 V on its own axis
[GND_clamp]
|Voltage   I(typ)   I(min)   I(max)
-1.2V     -103.3mA   -120.2mA   -92.98mA
-1.15V    -76.61mA   -93.07mA   -68.01mA
-1.125V   -65.16mA   -80.77mA   -58.26mA
-1.1V     -55.26mA   -69.51mA   -50.62mA
-1.05V    -40.58mA   -50.58mA   -40.74mA
-1V       -31.74mA   -36.89mA   -34.69mA
-950mV    -26.11mA   -27.84mA   -29.81mA
-900mV    -21.77mA   -21.87mA   -25.27mA
-700mV    -7.829mA   -8.229mA   -9mA
-575mV    -2.02mA    -2.934mA   -2.007mA
-475mV    -11.54uA   -619.3uA   239.8uA
1.2V      0A         0A         0A
[POWER_clamp]
|Voltage   I(typ)   I(min)   I(max)
-1.175V   130.7mA    154.1mA    117.7mA
-1.125V   98.64mA    122.4mA    85.59mA
-1.075V   70.56mA    93.38mA    59.18mA
-1.05V    58.62mA    80.24mA    49.1mA
-1V       40.18mA    57.41mA    36.11mA
-950mV    29.26mA    40.08mA    30.16mA
-900mV    23.69mA    28.51mA    27.01mA
-850mV    20.62mA    21.62mA    24.61mA
-775mV    17.48mA    16.22mA    21.3mA
-400mV    6.295mA    5.738mA    7.499mA
400mV     -5.968mA   -5.257mA   -7.147mA
2.4V      -28.99mA   -26.21mA   -34.74mA
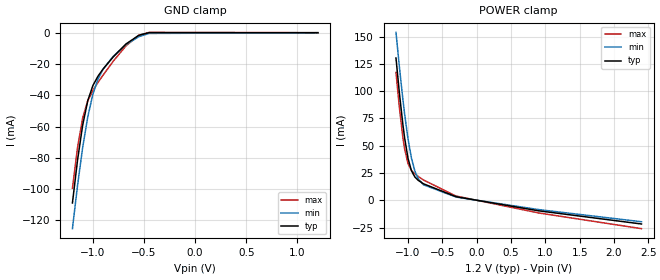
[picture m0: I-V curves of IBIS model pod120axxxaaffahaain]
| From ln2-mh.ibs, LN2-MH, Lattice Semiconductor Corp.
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|   Model pod120axxxaaffahaain
[Model] pod120axxxaaffahaain
Model_type Input
Polarity   Non-Inverting
Enable   Active-High
Vinl =  0.800V
Vinh =  1.000V
C_comp   2.000pF   1.500pF   2.500pF
[Temperature Range]   25.000   0.125k   -40.000
[Voltage Range]   1.200V   1.160V   1.240V
[C Comp Corner]
C_comp   2.000pF   1.500pF   2.500pF
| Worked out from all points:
|   GND clamp passes 1 mA (typ) near -0.53 V on its own axis
|   POWER clamp passes 1 mA (typ) near -0.09 V on its own axis
[GND_clamp]
|Voltage   I(typ)   I(min)   I(max)
-1.2V     -108.9mA   -125.3mA   -99.47mA
-1.15V    -81.48mA   -97.65mA   -73.38mA
-1.1V     -59.18mA   -73.46mA   -54.53mA
-1.05V    -43.46mA   -53.8mA    -43.53mA
-1V       -33.83mA   -39.35mA   -36.95mA
-950mV    -27.79mA   -29.67mA   -31.82mA
-900mV    -23.2mA    -23.3mA    -27.09mA
-800mV    -15.4mA    -15.03mA   -18.15mA
-675mV    -7.142mA   -7.608mA   -8.302mA
-550mV    -1.617mA   -2.503mA   -1.605mA
-450mV    19.72uA    -459.9uA   197.7uA
1.2V      0A         0A         0A
[POWER_clamp]
|Voltage   I(typ)   I(min)   I(max)
-1.175V   130.3mA    153.8mA    117.1mA
-1.125V   97.96mA    121.9mA    84.68mA
-1.075V   69.57mA    92.69mA    57.76mA
-1.05V    57.43mA    79.43mA    47.35mA
-1V       38.51mA    56.32mA    33.73mA
-950mV    27.19mA    38.66mA    27.48mA
-900mV    21.43mA    26.81mA    24.3mA
-850mV    18.32mA    19.74mA    21.93mA
-775mV    15.23mA    14.28mA    18.71mA
-300mV    3.373mA    3.062mA    3.999mA
900mV     -9.505mA   -8.383mA   -11.46mA
2.4V      -21.58mA   -19.53mA   -25.86mA
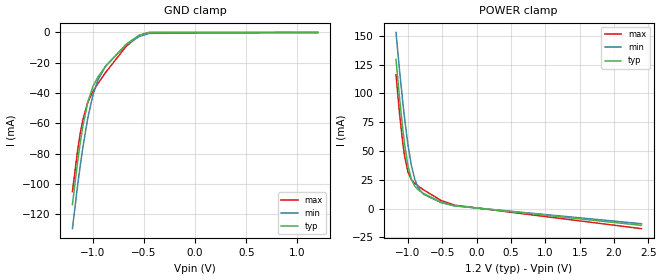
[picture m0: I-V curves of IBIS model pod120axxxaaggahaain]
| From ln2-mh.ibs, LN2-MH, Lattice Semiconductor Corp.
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|   Model pod120axxxaaggahaain
[Model] pod120axxxaaggahaain
Model_type Input
Polarity   Non-Inverting
Enable   Active-High
Vinl =  0.800V
Vinh =  1.000V
C_comp   2.000pF   1.500pF   2.500pF
[Temperature Range]   25.000   0.125k   -40.000
[Voltage Range]   1.200V   1.160V   1.240V
[C Comp Corner]
C_comp   2.000pF   1.500pF   2.500pF
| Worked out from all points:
|   GND clamp passes 1 mA (typ) near -0.51 V on its own axis
|   POWER clamp passes 1 mA (typ) near -0.13 V on its own axis
[GND_clamp]
|Voltage   I(typ)   I(min)   I(max)
-1.2V     -113.7mA   -129.6mA   -105.2mA
-1.15V    -85.71mA   -101.5mA   -78.22mA
-1.125V   -73.45mA   -88.68mA   -67.17mA
-1.1V     -62.64mA   -76.83mA   -58.17mA
-1.05V    -46.05mA   -56.58mA   -46.13mA
-1V       -35.75mA   -41.51mA   -39.05mA
-950mV    -29.32mA   -31.32mA   -33.67mA
-875mV    -22.37mA   -22.03mA   -26.38mA
-675mV    -7.799mA   -8.177mA   -9.21mA
-550mV    -1.934mA   -2.798mA   -2.053mA
-450mV    -96.61uA   -588.7uA   45.82uA
1.2V      0A         0A         0A
[POWER_clamp]
|Voltage   I(typ)   I(min)   I(max)
-1.175V   129.5mA    153mA      116.2mA
-1.125V   97.03mA    121mA      83.56mA
-1.075V   68.42mA    91.73mA    56.28mA
-1.05V    56.13mA    78.39mA    45.61mA
-1V       36.88mA    55.09mA    31.51mA
-950mV    25.25mA    37.21mA    25.02mA
-900mV    19.35mA    25.15mA    21.8mA
-850mV    16.21mA    17.96mA    19.48mA
-775mV    13.18mA    12.47mA    16.34mA
-525mV    5.782mA    5.278mA    7.21mA
-325mV    2.525mA    2.34mA     2.99mA
2.4V      -14.56mA   -13.17mA   -17.45mA
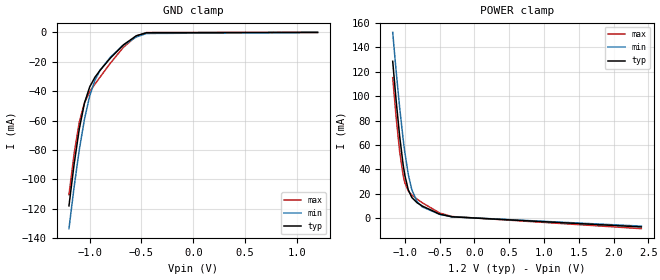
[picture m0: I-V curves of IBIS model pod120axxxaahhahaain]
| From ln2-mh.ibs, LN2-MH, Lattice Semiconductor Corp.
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|   Model pod120axxxaahhahaain
[Model] pod120axxxaahhahaain
Model_type Input
Polarity   Non-Inverting
Enable   Active-High
Vinl =  0.800V
Vinh =  1.000V
C_comp   2.000pF   1.500pF   2.500pF
[Temperature Range]   25.000   0.125k   -40.000
[Voltage Range]   1.200V   1.160V   1.240V
[C Comp Corner]
C_comp   2.000pF   1.500pF   2.500pF
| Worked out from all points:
|   GND clamp passes 1 mA (typ) near -0.50 V on its own axis
|   POWER clamp passes 1 mA (typ) near -0.27 V on its own axis
[GND_clamp]
|Voltage   I(typ)   I(min)   I(max)
-1.2V     -118.1mA   -133.6mA   -110.5mA
-1.15V    -89.52mA   -105.1mA   -82.46mA
-1.1V     -65.59mA   -79.86mA   -60.98mA
-1.05V    -48.06mA   -58.98mA   -47.8mA
-1V       -37.15mA   -43.31mA   -40.46mA
-950mV    -30.6mA    -32.72mA   -35.28mA
-900mV    -25.83mA   -25.82mA   -30.47mA
-800mV    -17.48mA   -16.87mA   -20.92mA
-675mV    -8.509mA   -8.787mA   -10.2mA
-550mV    -2.282mA   -3.118mA   -2.554mA
-450mV    -221.8uA   -729.4uA   -121.3uA
1.2V      0A         0A         0A
[POWER_clamp]
|Voltage   I(typ)   I(min)   I(max)
-1.175V   128.6mA    152.3mA    115.2mA
-1.125V   96.01mA    120.1mA    82.36mA
-1.075V   67.16mA    90.69mA    54.67mA
-1.025V   43.95mA    64.9mA     35.2mA
-1V       35.08mA    53.76mA    29.08mA
-950mV    23.12mA    35.63mA    22.32mA
-900mV    17.05mA    23.36mA    19.05mA
-825mV    12.77mA    13.67mA    15.73mA
-750mV    10.07mA    9.382mA    12.75mA
-500mV    3.401mA    3.223mA    4.362mA
-325mV    1.246mA    1.227mA    1.472mA
2.4V      -7.069mA   -6.418mA   -8.481mA
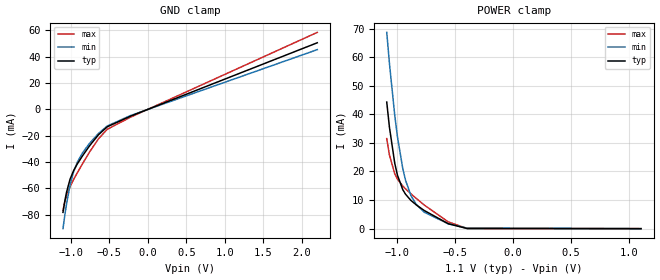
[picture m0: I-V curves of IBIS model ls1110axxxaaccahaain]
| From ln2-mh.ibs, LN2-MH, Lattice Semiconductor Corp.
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|   Model ls1110axxxaaccahaain
[Model] ls1110axxxaaccahaain
Model_type Input
Polarity   Non-Inverting
Enable   Active-High
Vinl =  0.200V
Vinh =  0.300V
C_comp   2.000pF   1.500pF   2.500pF
[Temperature Range]   25.000   0.125k   -40.000
[Voltage Range]   1.100V   1.070V   1.130V
[C Comp Corner]
C_comp   2.000pF   1.500pF   2.500pF
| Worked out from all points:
|   GND clamp passes 1 mA (typ) near -0.04 V on its own axis
|   POWER clamp passes 1 mA (typ) near -0.51 V on its own axis
[GND_clamp]
|Voltage   I(typ)   I(min)   I(max)
-1.1V     -78.33mA   -90.7mA    -76.76mA
-1.077V   -69.95mA   -80.8mA    -70.43mA
-1.054V   -63.03mA   -71.95mA   -65.59mA
-1.008V   -53.08mA   -57.58mA   -58.66mA
-962mV    -46.59mA   -47.42mA   -53.31mA
-916mV    -41.69mA   -40.41mA   -48.43mA
-847mV    -35.4mA    -33.14mA   -41.4mA
-755mV    -27.73mA   -25.86mA   -32.44mA
-640mV    -19.38mA   -18.38mA   -22.48mA
-525mV    -13.27mA   -12.68mA   -15.17mA
-226mV    -5.291mA   -4.798mA   -6.082mA
2.2V      50.54mA    45.32mA    58.42mA
[POWER_clamp]
|Voltage   I(typ)   I(min)   I(max)
-1.085V   44.29mA    68.67mA    31.51mA
-1.062V   35.54mA    57.9mA     25.79mA
-1.016V   22.84mA    39.56mA    19.17mA
-993mV    18.72mA    32.16mA    17.34mA
-947mV    13.63mA    20.97mA    14.91mA
-924mV    12.07mA    17.02mA    13.96mA
-878mV    9.916mA    11.64mA    12.23mA
-832mV    8.338mA    8.48mA     10.6mA
-763mV    6.356mA    5.767mA    8.274mA
-556mV    1.724mA    1.672mA    2.36mA
-395mV    56.01uA    193.2uA    81.38uA
1.1V      0A         0A         0A
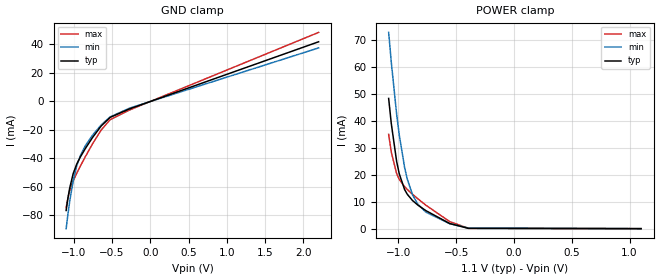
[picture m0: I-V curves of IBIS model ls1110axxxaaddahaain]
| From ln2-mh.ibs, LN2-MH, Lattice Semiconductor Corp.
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|   Model ls1110axxxaaddahaain
[Model] ls1110axxxaaddahaain
Model_type Input
Polarity   Non-Inverting
Enable   Active-High
Vinl =  0.200V
Vinh =  0.300V
C_comp   2.000pF   1.500pF   2.500pF
[Temperature Range]   25.000   0.125k   -40.000
[Voltage Range]   1.100V   1.070V   1.130V
[C Comp Corner]
C_comp   2.000pF   1.500pF   2.500pF
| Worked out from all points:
|   GND clamp passes 1 mA (typ) near -0.05 V on its own axis
|   POWER clamp passes 1 mA (typ) near -0.50 V on its own axis
[GND_clamp]
|Voltage   I(typ)   I(min)   I(max)
-1.1V     -76.53mA   -89.25mA   -74.42mA
-1.077V   -67.96mA   -79.24mA   -67.85mA
-1.054V   -60.87mA   -70.28mA   -62.83mA
-1.008V   -50.65mA   -55.68mA   -55.75mA
-962mV    -44.05mA   -45.33mA   -50.39mA
-916mV    -39.14mA   -38.22mA   -45.54mA
-847mV    -32.89mA   -30.93mA   -38.59mA
-755mV    -25.33mA   -23.72mA   -29.74mA
-640mV    -17.13mA   -16.39mA   -19.94mA
-525mV    -11.24mA   -10.89mA   -12.85mA
-272mV    -5.266mA   -4.782mA   -6.058mA
2.2V      41.78mA    37.47mA    48.35mA
[POWER_clamp]
|Voltage   I(typ)   I(min)   I(max)
-1.085V   48.34mA    72.86mA    35.01mA
-1.062V   38.96mA    61.73mA    28.37mA
-1.016V   24.99mA    42.56mA    20.46mA
-993mV    20.33mA    34.72mA    18.3mA
-947mV    14.53mA    22.7mA     15.57mA
-924mV    12.78mA    18.4mA     14.56mA
-878mV    10.42mA    12.51mA    12.76mA
-832mV    8.748mA    9.049mA    11.09mA
-763mV    6.694mA    6.125mA    8.705mA
-556mV    1.9mA      1.829mA    2.606mA
-395mV    105uA      252.7uA    142.4uA
1.1V      0A         0A         0A
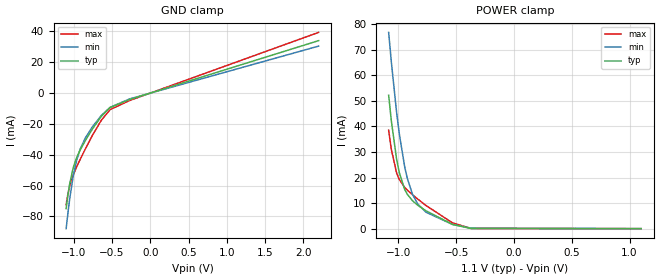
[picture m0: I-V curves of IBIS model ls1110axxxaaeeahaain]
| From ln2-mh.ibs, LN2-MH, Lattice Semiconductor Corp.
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|   Model ls1110axxxaaeeahaain
[Model] ls1110axxxaaeeahaain
Model_type Input
Polarity   Non-Inverting
Enable   Active-High
Vinl =  0.200V
Vinh =  0.300V
C_comp   2.000pF   1.500pF   2.500pF
[Temperature Range]   25.000   0.125k   -40.000
[Voltage Range]   1.100V   1.070V   1.130V
[C Comp Corner]
C_comp   2.000pF   1.500pF   2.500pF
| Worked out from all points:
|   GND clamp passes 1 mA (typ) near -0.06 V on its own axis
|   POWER clamp passes 1 mA (typ) near -0.49 V on its own axis
[GND_clamp]
|Voltage   I(typ)   I(min)   I(max)
-1.1V     -74.95mA   -87.97mA   -72.37mA
-1.077V   -66.23mA   -77.87mA   -65.59mA
-1.054V   -58.98mA   -68.8mA    -60.4mA
-1.008V   -48.52mA   -54mA      -53.16mA
-962mV    -41.81mA   -43.49mA   -47.78mA
-916mV    -36.88mA   -36.28mA   -42.97mA
-847mV    -30.67mA   -28.96mA   -36.08mA
-755mV    -23.2mA    -21.81mA   -27.33mA
-640mV    -15.13mA   -14.61mA   -17.67mA
-525mV    -9.436mA   -9.292mA   -10.78mA
-272mV    -4.278mA   -3.883mA   -4.922mA
2.2V      33.93mA    30.39mA    39.27mA
[POWER_clamp]
|Voltage   I(typ)   I(min)   I(max)
-1.085V   52.16mA    76.73mA    38.51mA
-1.062V   42.24mA    65.28mA    31.02mA
-1.016V   27.1mA     45.38mA    21.77mA
-993mV    21.93mA    37.14mA    19.24mA
-947mV    15.42mA    24.36mA    16.17mA
-924mV    13.47mA    19.73mA    15.09mA
-878mV    10.89mA    13.34mA    13.23mA
-832mV    9.125mA    9.591mA    11.52mA
-763mV    7.003mA    6.459mA    9.086mA
-533mV    1.661mA    1.646mA    2.285mA
-372mV    62.23uA    195.1uA    78.98uA
1.1V      0A         0A         0A
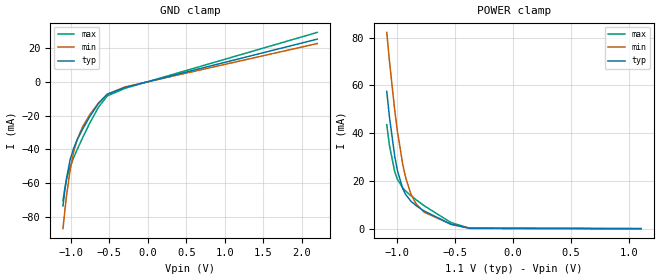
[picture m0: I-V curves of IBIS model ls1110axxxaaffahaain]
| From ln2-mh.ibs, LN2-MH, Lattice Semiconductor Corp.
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|   Model ls1110axxxaaffahaain
[Model] ls1110axxxaaffahaain
Model_type Input
Polarity   Non-Inverting
Enable   Active-High
Vinl =  0.200V
Vinh =  0.300V
C_comp   2.000pF   1.500pF   2.500pF
[Temperature Range]   25.000   0.125k   -40.000
[Voltage Range]   1.100V   1.070V   1.130V
[C Comp Corner]
C_comp   2.000pF   1.500pF   2.500pF
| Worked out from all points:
|   GND clamp passes 1 mA (typ) near -0.09 V on its own axis
|   POWER clamp passes 1 mA (typ) near -0.48 V on its own axis
[GND_clamp]
|Voltage   I(typ)   I(min)   I(max)
-1.1V     -73.41mA   -86.81mA   -70.26mA
-1.077V   -64.47mA   -76.58mA   -63.19mA
-1.054V   -57.01mA   -67.37mA   -57.79mA
-1.008V   -46.21mA   -52.28mA   -50.32mA
-962mV    -39.34mA   -41.53mA   -44.91mA
-916mV    -34.38mA   -34.18mA   -40.12mA
-847mV    -28.21mA   -26.8mA    -33.3mA
-755mV    -20.83mA   -19.7mA    -24.66mA
-640mV    -12.9mA    -12.63mA   -15.14mA
-525mV    -7.407mA   -7.505mA   -8.456mA
-295mV    -3.432mA   -3.128mA   -3.952mA
2.2V      25.09mA    22.49mA    29.07mA
[POWER_clamp]
|Voltage   I(typ)   I(min)   I(max)
-1.085V   57.54mA    82.21mA    43.56mA
-1.062V   46.9mA     70.32mA    34.95mA
-1.016V   30.2mA     49.44mA    23.76mA
-993mV    24.29mA    40.66mA    20.64mA
-947mV    16.71mA    26.8mA     17.01mA
-924mV    14.44mA    21.68mA    15.82mA
-878mV    11.52mA    14.54mA    13.85mA
-832mV    9.615mA    10.35mA    12.09mA
-763mV    7.398mA    6.902mA    9.587mA
-533mV    1.852mA    1.814mA    2.553mA
-372mV    108uA      253.3uA    136.4uA
1.1V      0A         0A         0A
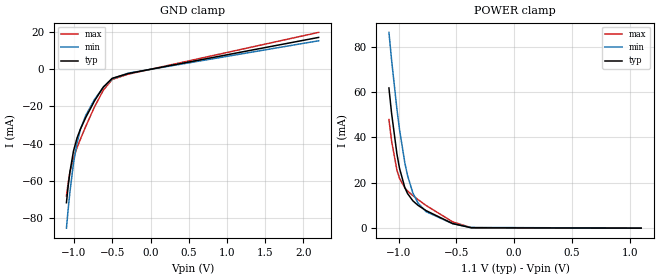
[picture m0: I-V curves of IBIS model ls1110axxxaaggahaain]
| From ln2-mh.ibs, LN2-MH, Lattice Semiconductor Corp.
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|   Model ls1110axxxaaggahaain
[Model] ls1110axxxaaggahaain
Model_type Input
Polarity   Non-Inverting
Enable   Active-High
Vinl =  0.200V
Vinh =  0.300V
C_comp   2.000pF   1.500pF   2.500pF
[Temperature Range]   25.000   0.125k   -40.000
[Voltage Range]   1.100V   1.070V   1.130V
[C Comp Corner]
C_comp   2.000pF   1.500pF   2.500pF
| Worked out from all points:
|   GND clamp passes 1 mA (typ) near -0.13 V on its own axis
|   POWER clamp passes 1 mA (typ) near -0.47 V on its own axis
[GND_clamp]
|Voltage   I(typ)   I(min)   I(max)
-1.1V     -71.87mA   -85.55mA   -68.28mA
-1.077V   -62.78mA   -75.23mA   -60.99mA
-1.054V   -55.16mA   -65.92mA   -55.39mA
-1.008V   -44.1mA    -50.62mA   -47.74mA
-962mV    -37.11mA   -39.7mA    -42.3mA
-916mV    -32.12mA   -32.24mA   -37.53mA
-847mV    -25.98mA   -24.83mA   -30.78mA
-732mV    -16.99mA   -16.26mA   -20.21mA
-617mV    -9.595mA   -9.675mA   -11.27mA
-502mV    -4.904mA   -5.178mA   -5.545mA
-295mV    -2.343mA   -2.14mA    -2.698mA
2.2V      17.12mA    15.32mA    19.84mA
[POWER_clamp]
|Voltage   I(typ)   I(min)   I(max)
-1.085V   61.79mA    86.32mA    47.89mA
-1.062V   50.64mA    74.13mA    38.42mA
-1.016V   32.78mA    52.55mA    25.61mA
-993mV    26.31mA    43.38mA    21.92mA
-947mV    17.84mA    28.73mA    17.73mA
-924mV    15.28mA    23.25mA    16.42mA
-878mV    12.05mA    15.53mA    14.35mA
-832mV    10.02mA    10.97mA    12.54mA
-763mV    7.725mA    7.27mA     9.989mA
-533mV    2.011mA    1.955mA    2.772mA
-372mV    150.5uA    304.4uA    188.9uA
1.1V      0A         0A         0A
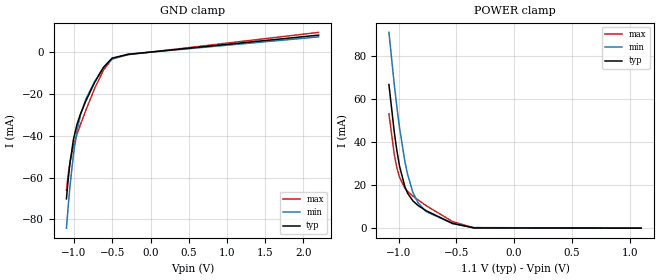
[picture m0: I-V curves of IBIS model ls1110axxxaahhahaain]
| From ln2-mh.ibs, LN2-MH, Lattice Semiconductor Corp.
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|   Model ls1110axxxaahhahaain
[Model] ls1110axxxaahhahaain
Model_type Input
Polarity   Non-Inverting
Enable   Active-High
Vinl =  0.200V
Vinh =  0.300V
C_comp   2.000pF   1.500pF   2.500pF
[Temperature Range]   25.000   0.125k   -40.000
[Voltage Range]   1.100V   1.070V   1.130V
[C Comp Corner]
C_comp   2.000pF   1.500pF   2.500pF
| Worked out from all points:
|   GND clamp passes 1 mA (typ) near -0.27 V on its own axis
|   POWER clamp passes 1 mA (typ) near -0.46 V on its own axis
[GND_clamp]
|Voltage   I(typ)   I(min)   I(max)
-1.1V     -70.15mA   -84.15mA   -66.08mA
-1.077V   -60.89mA   -73.72mA   -58.53mA
-1.054V   -53.08mA   -64.3mA    -52.72mA
-1.008V   -41.72mA   -48.77mA   -44.84mA
-962mV    -34.57mA   -37.64mA   -39.35mA
-916mV    -29.55mA   -30.07mA   -34.61mA
-847mV    -23.45mA   -22.61mA   -27.93mA
-732mV    -14.59mA   -14.12mA   -17.5mA
-617mV    -7.351mA   -7.689mA   -8.723mA
-502mV    -2.892mA   -3.406mA   -3.234mA
-295mV    -1.108mA   -1.027mA   -1.278mA
2.2V      8.093mA    7.263mA    9.402mA
[POWER_clamp]
|Voltage   I(typ)   I(min)   I(max)
-1.085V   66.78mA    91.02mA    53.14mA
-1.039V   44.73mA    66.84mA    34.34mA
-1.016V   35.93mA    56.16mA    28.03mA
-993mV    28.79mA    46.57mA    23.62mA
-947mV    19.24mA    31.02mA    18.64mA
-924mV    16.33mA    25.13mA    17.17mA
-878mV    12.7mA     16.72mA    14.95mA
-832mV    10.5mA     11.72mA    13.08mA
-763mV    8.103mA    7.701mA    10.47mA
-533mV    2.197mA    2.117mA    3.035mA
-349mV    107.2uA    245.1uA    126.2uA
1.1V      0A         0A         0A
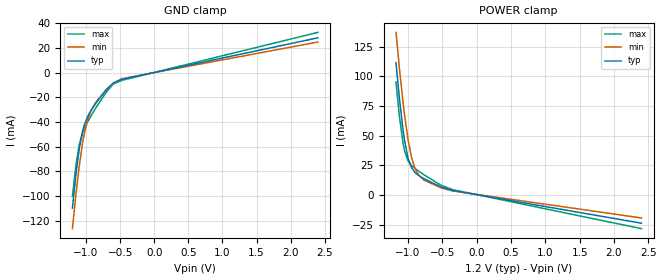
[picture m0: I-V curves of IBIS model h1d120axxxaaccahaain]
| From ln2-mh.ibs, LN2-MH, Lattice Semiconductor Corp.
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|   Model h1d120axxxaaccahaain
[Model] h1d120axxxaaccahaain
Model_type Input
Polarity   Non-Inverting
Enable   Active-High
Vinl =  0.500V
Vinh =  0.700V
C_comp   2.000pF   1.500pF   2.500pF
[Temperature Range]   25.000   0.125k   -40.000
[Voltage Range]   1.200V   1.160V   1.240V
[C Comp Corner]
C_comp   2.000pF   1.500pF   2.500pF
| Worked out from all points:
|   GND clamp passes 1 mA (typ) near -0.09 V on its own axis
|   POWER clamp passes 1 mA (typ) near -0.09 V on its own axis
[GND_clamp]
|Voltage   I(typ)   I(min)   I(max)
-1.2V     -109.8mA   -126.5mA   -100.3mA
-1.15V    -83.19mA   -99.28mA   -75.43mA
-1.1V     -61.92mA   -75.71mA   -58.18mA
-1.05V    -47.3mA    -56.79mA   -48.32mA
-1.025V   -42.31mA   -49.29mA   -45mA
-975mV    -35.33mA   -38.02mA   -39.61mA
-925mV    -30.39mA   -30.62mA   -34.8mA
-850mV    -24.22mA   -23.4mA    -27.95mA
-700mV    -13.62mA   -13.54mA   -15.51mA
-600mV    -8.252mA   -8.664mA   -9.105mA
-475mV    -5.391mA   -4.863mA   -6.216mA
2.4V      28.27mA    24.86mA    32.68mA
[POWER_clamp]
|Voltage   I(typ)   I(min)   I(max)
-1.175V   111.6mA    137.2mA    95.35mA
-1.125V   81.54mA    106.8mA    66.44mA
-1.075V   56.23mA    79.52mA    44.72mA
-1.05V    45.99mA    67.39mA    37.35mA
-1V       31.2mA     46.85mA    28.84mA
-950mV    23.18mA    31.97mA    24.92mA
-900mV    19.13mA    22.53mA    22.44mA
-850mV    16.7mA     17.07mA    20.31mA
-775mV    13.99mA    12.76mA    17.29mA
-525mV    6.828mA    6.147mA    8.382mA
-350mV    3.769mA    3.401mA    4.505mA
2.4V      -23.81mA   -19.42mA   -28.42mA
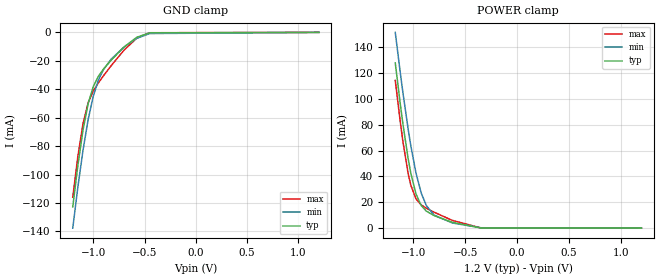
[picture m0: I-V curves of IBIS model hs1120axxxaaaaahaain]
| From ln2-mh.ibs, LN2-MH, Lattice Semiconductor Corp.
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|   Model hs1120axxxaaaaahaain
[Model] hs1120axxxaaaaahaain
Model_type Input
Polarity   Non-Inverting
Enable   Active-High
Vinl =  0.500V
Vinh =  0.700V
C_comp   2.000pF   1.500pF   2.500pF
[Temperature Range]   25.000   0.125k   -40.000
[Voltage Range]   1.200V   1.160V   1.240V
[C Comp Corner]
C_comp   2.000pF   1.500pF   2.500pF
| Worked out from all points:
|   GND clamp passes 1 mA (typ) near -0.50 V on its own axis
|   POWER clamp passes 1 mA (typ) near -0.45 V on its own axis
[GND_clamp]
|Voltage   I(typ)   I(min)   I(max)
-1.2V     -122.7mA   -137.7mA   -116mA
-1.15V    -93.48mA   -108.7mA   -87.06mA
-1.1V     -68.68mA   -82.93mA   -64.19mA
-1.05V    -50.06mA   -61.34mA   -49.53mA
-1V       -38.15mA   -44.88mA   -41.24mA
-950mV    -30.91mA   -33.54mA   -35.51mA
-900mV    -25.81mA   -26.1mA    -30.49mA
-825mV    -19.48mA   -18.8mA    -23.39mA
-700mV    -10.29mA   -10.29mA   -12.48mA
-575mV    -3.418mA   -4.142mA   -4.045mA
-450mV    -323.4uA   -814.3uA   -268.3uA
1.2V      0A         0A         0A
[POWER_clamp]
|Voltage   I(typ)   I(min)   I(max)
-1.175V   127.9mA    151.5mA    114.3mA
-1.125V   95.1mA     119.3mA    81.28mA
-1.1V     80mA       104.2mA    66.46mA
-1.05V    53.45mA    76.25mA    42.06mA
-1.025V   42.52mA    63.79mA    33.25mA
-975mV    26.42mA    42.64mA    22.65mA
-925mV    17.53mA    27.24mA    17.97mA
-875mV    13.15mA    17.46mA    15.37mA
-800mV    9.709mA    10.06mA    12.3mA
-625mV    4.479mA    4.015mA    6.021mA
-350mV    147.7uA    296.5uA    176.7uA
1.2V      0A         0A         0A
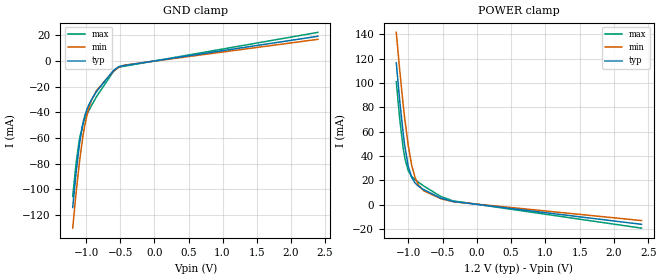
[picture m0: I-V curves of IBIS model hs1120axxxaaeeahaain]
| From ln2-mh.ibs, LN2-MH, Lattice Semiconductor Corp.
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|   Model hs1120axxxaaeeahaain
[Model] hs1120axxxaaeeahaain
Model_type Input
Polarity   Non-Inverting
Enable   Active-High
Vinl =  0.500V
Vinh =  0.700V
C_comp   2.000pF   1.500pF   2.500pF
[Temperature Range]   25.000   0.125k   -40.000
[Voltage Range]   1.200V   1.160V   1.240V
[C Comp Corner]
C_comp   2.000pF   1.500pF   2.500pF
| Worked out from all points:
|   GND clamp passes 1 mA (typ) near -0.13 V on its own axis
|   POWER clamp passes 1 mA (typ) near -0.14 V on its own axis
[GND_clamp]
|Voltage   I(typ)   I(min)   I(max)
-1.2V     -114.1mA   -130.2mA   -105.5mA
-1.15V    -86.69mA   -102.5mA   -79.32mA
-1.1V     -64.3mA    -78.23mA   -60.34mA
-1.05V    -48.48mA   -58.48mA   -49.17mA
-1.025V   -42.99mA   -50.55mA   -45.5mA
-975mV    -35.37mA   -38.51mA   -39.73mA
-925mV    -30.1mA    -30.57mA   -34.71mA
-850mV    -23.68mA   -22.9mA    -27.61mA
-600mV    -7.1mA     -7.611mA   -7.952mA
-525mV    -4.334mA   -4.89mA    -4.707mA
-450mV    -3.497mA   -3.173mA   -4.034mA
2.4V      19.38mA    17mA       22.42mA
[POWER_clamp]
|Voltage   I(typ)   I(min)   I(max)
-1.175V   116.6mA    141.6mA    101mA
-1.125V   85.57mA    110.6mA    70.64mA
-1.075V   58.98mA    82.58mA    46.72mA
-1.05V    47.96mA    69.98mA    38.11mA
-1V       31.52mA    48.4mA     27.74mA
-950mV    22.27mA    32.42mA    23.1mA
-900mV    17.66mA    22.06mA    20.45mA
-850mV    15.05mA    16.04mA    18.31mA
-775mV    12.29mA    11.38mA    15.32mA
-525mV    5.33mA     4.837mA    6.642mA
-350mV    2.61mA     2.397mA    3.117mA
2.4V      -16.2mA    -13.13mA   -19.34mA
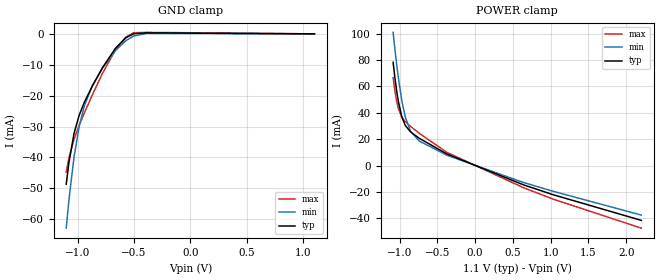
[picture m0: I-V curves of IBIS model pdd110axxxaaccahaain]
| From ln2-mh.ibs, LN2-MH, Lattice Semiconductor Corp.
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|   Model pdd110axxxaaccahaain
[Model] pdd110axxxaaccahaain
Model_type Input
Polarity   Non-Inverting
Enable   Active-High
Vinl =  0.700V
Vinh =  0.900V
C_comp   2.000pF   1.500pF   2.500pF
[Temperature Range]   25.000   0.125k   -40.000
[Voltage Range]   1.100V   1.070V   1.130V
[C Comp Corner]
C_comp   2.000pF   1.500pF   2.500pF
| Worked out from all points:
|   GND clamp passes 1 mA (typ) near -0.56 V on its own axis
|   POWER clamp passes 1 mA (typ) near -0.04 V on its own axis
[GND_clamp]
|Voltage   I(typ)   I(min)   I(max)
-1.1V     -48.64mA   -62.87mA   -44.77mA
-1.077V   -41.84mA   -54.09mA   -40.26mA
-1.031V   -32.24mA   -39.84mA   -34.1mA
-985mV    -26.31mA   -29.88mA   -29.58mA
-939mV    -22.11mA   -23.26mA   -25.56mA
-870mV    -16.97mA   -16.87mA   -19.86mA
-778mV    -10.92mA   -11mA      -12.73mA
-663mV    -4.629mA   -5.391mA   -5.151mA
-571mV    -1.244mA   -2.2mA     -1.062mA
-502mV    26.93uA    -707.7uA   356.1uA
-387mV    325uA      148uA      479.1uA
1.1V      0A         0A         0A
[POWER_clamp]
|Voltage   I(typ)   I(min)   I(max)
-1.085V   78.2mA     100.9mA    66.59mA
-1.062V   66.87mA    88.58mA    56.8mA
-1.039V   56.97mA    77.14mA    49.05mA
-1.016V   48.65mA    66.7mA     43.36mA
-970mV    36.91mA    49.3mA     36.7mA
-924mV    30.44mA    36.82mA    33.28mA
-855mV    25.6mA     26.04mA    29.74mA
-740mV    20.76mA    18.65mA    24.48mA
-372mV    8.768mA    7.848mA    10.01mA
640mV     -14.54mA   -12.76mA   -16.71mA
1.031V    -22mA      -19.39mA   -25.33mA
2.2V      -41.45mA   -37.45mA   -47.33mA
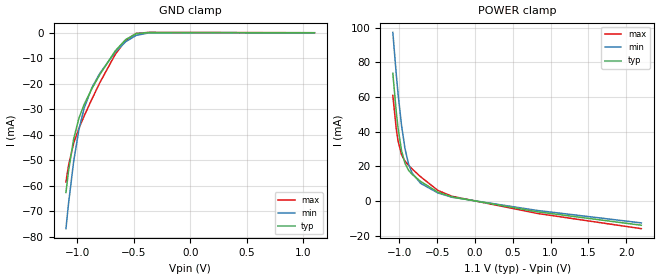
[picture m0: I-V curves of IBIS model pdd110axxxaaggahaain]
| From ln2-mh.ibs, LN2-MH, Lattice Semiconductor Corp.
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|   Model pdd110axxxaaggahaain
[Model] pdd110axxxaaggahaain
Model_type Input
Polarity   Non-Inverting
Enable   Active-High
Vinl =  0.700V
Vinh =  0.900V
C_comp   2.000pF   1.500pF   2.500pF
[Temperature Range]   25.000   0.125k   -40.000
[Voltage Range]   1.100V   1.070V   1.130V
[C Comp Corner]
C_comp   2.000pF   1.500pF   2.500pF
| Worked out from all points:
|   GND clamp passes 1 mA (typ) near -0.51 V on its own axis
|   POWER clamp passes 1 mA (typ) near -0.13 V on its own axis
[GND_clamp]
|Voltage   I(typ)   I(min)   I(max)
-1.1V     -62.61mA   -76.8mA    -58.46mA
-1.077V   -54.11mA   -66.87mA   -51.96mA
-1.031V   -41.44mA   -50.19mA   -43.2mA
-985mV    -33.47mA   -37.95mA   -37.43mA
-939mV    -28.11mA   -29.55mA   -32.64mA
-870mV    -21.9mA    -21.51mA   -25.99mA
-801mV    -16.45mA   -15.96mA   -19.66mA
-663mV    -7.083mA   -7.54mA    -8.421mA
-571mV    -2.664mA   -3.511mA   -2.99mA
-479mV    -379.1uA   -1.034mA   -249.4uA
-364mV    84.08uA    -33.64uA   136.2uA
1.1V      0A         0A         0A
[POWER_clamp]
|Voltage   I(typ)   I(min)   I(max)
-1.085V   73.72mA    97.3mA     60.96mA
-1.039V   51.23mA    72.83mA    41.42mA
-1.016V   42.19mA    61.98mA    34.73mA
-970mV    29.06mA    43.64mA    26.8mA
-924mV    21.72mA    30.24mA    23.02mA
-878mV    17.85mA    21.52mA    20.64mA
-832mV    15.49mA    16.27mA    18.63mA
-717mV    11.34mA    10.2mA     13.98mA
-487mV    5.055mA    4.654mA    6.091mA
-303mV    2.423mA    2.21mA     2.761mA
824mV     -6.167mA   -5.408mA   -7.115mA
2.2V      -13.93mA   -12.59mA   -15.91mA
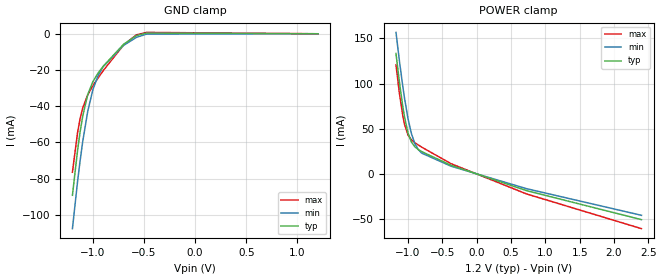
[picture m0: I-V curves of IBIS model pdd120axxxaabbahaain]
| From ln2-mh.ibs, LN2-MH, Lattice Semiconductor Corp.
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|   Model pdd120axxxaabbahaain
[Model] pdd120axxxaabbahaain
Model_type Input
Polarity   Non-Inverting
Enable   Active-High
Vinl =  0.800V
Vinh =  1.000V
C_comp   2.000pF   1.500pF   2.500pF
[Temperature Range]   25.000   0.125k   -40.000
[Voltage Range]   1.200V   1.160V   1.240V
[C Comp Corner]
C_comp   2.000pF   1.500pF   2.500pF
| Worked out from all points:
|   GND clamp passes 1 mA (typ) near -0.57 V on its own axis
|   POWER clamp passes 1 mA (typ) near -0.04 V on its own axis
[GND_clamp]
|Voltage   I(typ)   I(min)   I(max)
-1.2V     -89.18mA   -107.6mA   -76.46mA
-1.15V    -64.46mA   -81.72mA   -54.69mA
-1.125V   -54.21mA   -70.19mA   -46.86mA
-1.1V     -45.63mA   -59.77mA   -41.04mA
-1.05V    -33.51mA   -42.72mA   -33.62mA
-1V       -26.42mA   -30.87mA   -28.69mA
-950mV    -21.76mA   -23.24mA   -24.46mA
-900mV    -18mA      -18.23mA   -20.44mA
-700mV    -5.803mA   -6.464mA   -6.234mA
-575mV    -1.006mA   -1.997mA   -603uA
-475mV    387.9uA    -185uA     755.3uA
1.2V      0A         0A         0A
[POWER_clamp]
|Voltage   I(typ)   I(min)   I(max)
-1.175V   133.2mA    156.5mA    120.5mA
-1.125V   101.6mA    125mA      89.21mA
-1.075V   74.26mA    96.4mA     64.08mA
-1.05V    62.79mA    83.52mA    54.78mA
-1V       45.42mA    61.31mA    43.18mA
-950mV    35.35mA    44.67mA    37.81mA
-900mV    30.16mA    33.68mA    34.71mA
-850mV    27.13mA    27.12mA    32.18mA
-800mV    24.85mA    23.2mA     29.77mA
-375mV    9.808mA    8.811mA    11.61mA
725mV     -18.19mA   -16.03mA   -21.82mA
2.4V      -50.25mA   -45.46mA   -60.2mA
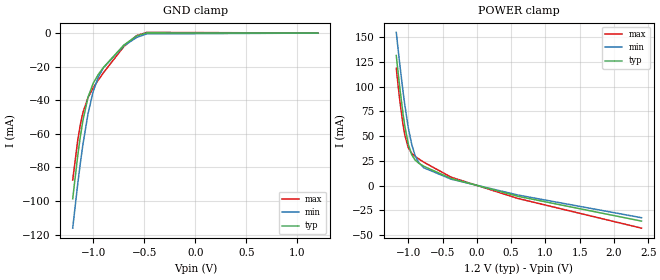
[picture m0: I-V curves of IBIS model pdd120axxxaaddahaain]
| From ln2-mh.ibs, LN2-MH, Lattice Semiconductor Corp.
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|   Model pdd120axxxaaddahaain
[Model] pdd120axxxaaddahaain
Model_type Input
Polarity   Non-Inverting
Enable   Active-High
Vinl =  0.800V
Vinh =  1.000V
C_comp   2.000pF   1.500pF   2.500pF
[Temperature Range]   25.000   0.125k   -40.000
[Voltage Range]   1.200V   1.160V   1.240V
[C Comp Corner]
C_comp   2.000pF   1.500pF   2.500pF
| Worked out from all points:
|   GND clamp passes 1 mA (typ) near -0.55 V on its own axis
|   POWER clamp passes 1 mA (typ) near -0.05 V on its own axis
[GND_clamp]
|Voltage   I(typ)   I(min)   I(max)
-1.2V     -98.61mA   -116.1mA   -87.45mA
-1.15V    -72.55mA   -89.3mA    -63.48mA
-1.125V   -61.48mA   -77.25mA   -54.35mA
-1.1V     -52.01mA   -66.26mA   -47.33mA
-1.05V    -38.18mA   -47.94mA   -38.33mA
-1V       -29.94mA   -34.86mA   -32.68mA
-950mV    -24.65mA   -26.29mA   -28.02mA
-900mV    -20.51mA   -20.65mA   -23.66mA
-700mV    -7.144mA   -7.633mA   -8.066mA
-575mV    -1.672mA   -2.615mA   -1.523mA
-475mV    126.4uA    -470.4uA   418.7uA
1.2V      0A         0A         0A
[POWER_clamp]
|Voltage   I(typ)   I(min)   I(max)
-1.175V   131.5mA    154.9mA    118.6mA
-1.125V   99.59mA    123.2mA    86.74mA
-1.075V   71.74mA    94.35mA    60.73mA
-1.05V    59.95mA    81.3mA     50.9mA
-1V       41.85mA    58.67mA    38.38mA
-950mV    31.21mA    41.56mA    32.62mA
-900mV    25.78mA    30.18mA    29.5mA
-850mV    22.72mA    23.4mA     27.06mA
-775mV    19.52mA    18.03mA    23.65mA
-375mV    7.107mA    6.438mA    8.431mA
600mV     -10.91mA   -9.62mA    -13.1mA
2.4V      -35.95mA   -32.53mA   -43.08mA
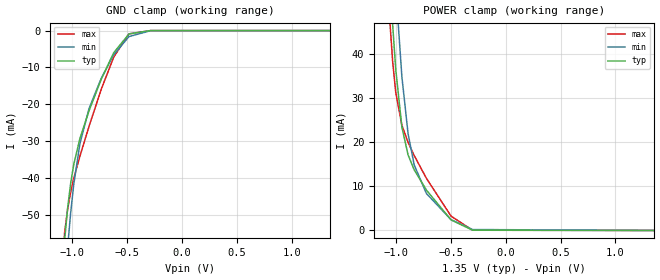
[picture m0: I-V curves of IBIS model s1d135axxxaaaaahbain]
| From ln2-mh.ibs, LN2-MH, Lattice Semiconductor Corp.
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|   Model s1d135axxxaaaaahbain
[Model] s1d135axxxaaaaahbain
Model_type Input
Polarity   Non-Inverting
Enable   Active-High
Vinl =  0.575V
Vinh =  0.775V
C_comp   2.000pF   1.500pF   2.500pF
[Temperature Range]   25.000   0.125k   -40.000
[Voltage Range]   1.350V   1.310V   1.390V
[C Comp Corner]
C_comp   2.000pF   1.500pF   2.500pF
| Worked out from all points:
|   GND clamp passes 1 mA (typ) near -0.49 V on its own axis
|   POWER clamp passes 1 mA (typ) near -0.42 V on its own axis
[GND_clamp]
|Voltage   I(typ)   I(min)   I(max)
-1.35V    -224.7mA   -236.3mA   -220.2mA
-1.07V    -57.07mA   -69.75mA   -54.91mA
-1.042V   -48.17mA   -58.73mA   -48.43mA
-1.014V   -41.37mA   -49.36mA   -43.74mA
-986mV    -36.28mA   -41.67mA   -40.08mA
-930mV    -29.25mA   -30.69mA   -34.04mA
-846mV    -21.68mA   -21.08mA   -25.9mA
-734mV    -13.09mA   -12.84mA   -15.8mA
-622mV    -6.012mA   -6.571mA   -7.208mA
-482mV    -893.5uA   -1.618mA   -887uA
-286mV    -2.505uA   -30.54uA   -560.5nA
1.35V     0A         0A         0A
[POWER_clamp]
|Voltage   I(typ)   I(min)   I(max)
-1.338V   248.7mA    268.2mA    238.6mA
-1.086V   73.41mA    96.99mA    61.03mA
-1.058V   58.94mA    81.58mA    48.12mA
-1.03V    46.49mA    67.45mA    38.13mA
-1.002V   36.4mA     54.81mA    31.18mA
-946mV    23.36mA    34.76mA    23.78mA
-890mV    17.11mA    21.96mA    19.93mA
-834mV    13.71mA    14.82mA    16.95mA
-722mV    9.115mA    8.346mA    11.77mA
-498mV    2.398mA    2.45mA     3.247mA
-302mV    67.77uA    212.2uA    59.32uA
1.35V     0A         0A         0A
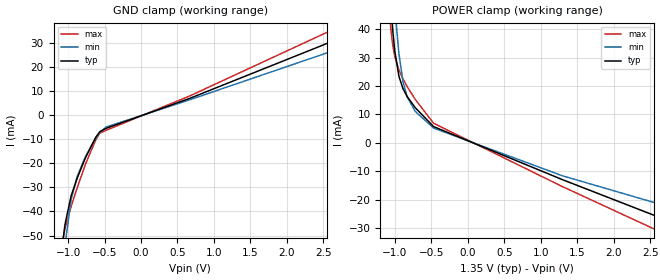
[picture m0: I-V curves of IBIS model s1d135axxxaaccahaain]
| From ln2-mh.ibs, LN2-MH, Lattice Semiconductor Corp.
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|   Model s1d135axxxaaccahaain
[Model] s1d135axxxaaccahaain
Model_type Input
Polarity   Non-Inverting
Enable   Active-High
Vinl =  0.575V
Vinh =  0.775V
C_comp   2.000pF   1.500pF   2.500pF
[Temperature Range]   25.000   0.125k   -40.000
[Voltage Range]   1.350V   1.310V   1.390V
[C Comp Corner]
C_comp   2.000pF   1.500pF   2.500pF
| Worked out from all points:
|   GND clamp passes 1 mA (typ) near -0.09 V on its own axis
|   POWER clamp passes 1 mA (typ) near -0.09 V on its own axis
[GND_clamp]
|Voltage   I(typ)   I(min)   I(max)
-1.35V    -205.9mA   -220.2mA   -196.9mA
-1.098V   -60.68mA   -74.23mA   -57.32mA
-1.07V    -51.95mA   -63.21mA   -51.39mA
-1.042V   -45.28mA   -53.8mA    -47.07mA
-958mV    -33.42mA   -34.95mA   -37.89mA
-874mV    -26.05mA   -25.31mA   -30.06mA
-762mV    -17.67mA   -17.15mA   -20.33mA
-622mV    -9.226mA   -9.56mA    -10.29mA
-566mV    -6.852mA   -7.302mA   -7.472mA
-482mV    -5.451mA   -4.909mA   -6.292mA
666mV     7.016mA    6.431mA    8.013mA
2.7V      31.68mA    27.5mA     36.59mA
[POWER_clamp]
|Voltage   I(typ)   I(min)   I(max)
-1.338V   225.8mA    248.4mA    211.1mA
-1.086V   61.16mA    84.88mA    49.21mA
-1.058V   49.17mA    70.93mA    40.34mA
-1.03V    39.49mA    58.45mA    34.29mA
-1.002V   32.19mA    47.62mA    30.36mA
-946mV    23.45mA    31.34mA    25.69mA
-890mV    19.09mA    21.62mA    22.51mA
-834mV    16.36mA    16.27mA    19.85mA
-722mV    12.39mA    11.06mA    15.3mA
-470mV    5.717mA    5.212mA    6.898mA
1.294V    -12.93mA   -11.58mA   -15.37mA
2.7V      -26.98mA   -22.11mA   -32.06mA
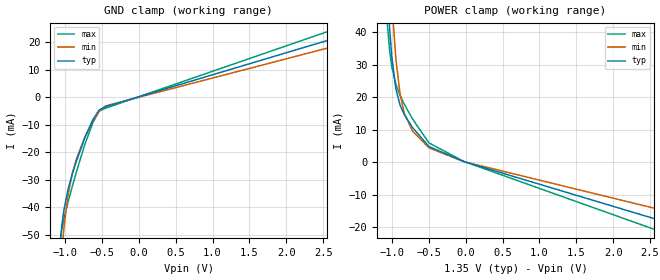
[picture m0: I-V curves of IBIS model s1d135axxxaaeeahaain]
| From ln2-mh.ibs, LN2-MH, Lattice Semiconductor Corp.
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|   Model s1d135axxxaaeeahaain
[Model] s1d135axxxaaeeahaain
Model_type Input
Polarity   Non-Inverting
Enable   Active-High
Vinl =  0.575V
Vinh =  0.775V
C_comp   2.000pF   1.500pF   2.500pF
[Temperature Range]   25.000   0.125k   -40.000
[Voltage Range]   1.350V   1.310V   1.390V
[C Comp Corner]
C_comp   2.000pF   1.500pF   2.500pF
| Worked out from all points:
|   GND clamp passes 1 mA (typ) near -0.13 V on its own axis
|   POWER clamp passes 1 mA (typ) near -0.14 V on its own axis
[GND_clamp]
|Voltage   I(typ)   I(min)   I(max)
-1.35V    -212.1mA   -225.5mA   -204.5mA
-1.07V    -53.72mA   -65.42mA   -52.72mA
-1.042V   -46.38mA   -55.5mA    -47.83mA
-1.014V   -40.87mA   -47.24mA   -44.07mA
-958mV    -33.36mA   -35.3mA    -37.97mA
-902mV    -27.99mA   -27.76mA   -32.48mA
-846mV    -23.32mA   -22.52mA   -27.22mA
-734mV    -14.93mA   -14.64mA   -17.37mA
-622mV    -8.134mA   -8.555mA   -9.216mA
-538mV    -4.698mA   -5.265mA   -5.091mA
-454mV    -3.515mA   -3.226mA   -4.06mA
2.7V      21.71mA    18.8mA     25.09mA
[POWER_clamp]
|Voltage   I(typ)   I(min)   I(max)
-1.338V   232.8mA    254.5mA    219.5mA
-1.086V   64.39mA    88.31mA    51.81mA
-1.058V   51.5mA     73.84mA    41.5mA
-1.03V    40.85mA    60.78mA    34.18mA
-1.002V   32.6mA     49.31mA    29.37mA
-946mV    22.51mA    31.75mA    23.96mA
-890mV    17.59mA    21.03mA    20.59mA
-834mV    14.69mA    15.13mA    17.87mA
-722mV    10.69mA    9.602mA    13.34mA
-498mV    4.812mA    4.415mA    5.925mA
-22mV     162.5uA    142.1uA    193.2uA
2.7V      -18.35mA   -14.96mA   -21.82mA
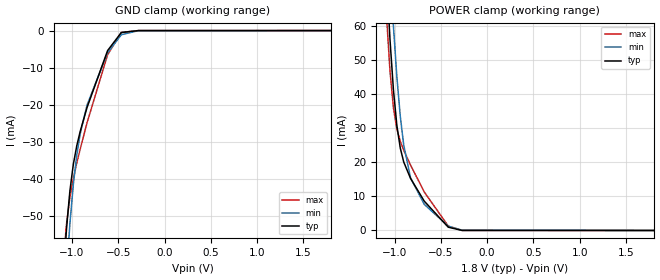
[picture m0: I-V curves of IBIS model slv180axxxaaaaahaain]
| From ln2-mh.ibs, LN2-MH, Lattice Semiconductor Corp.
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|   Model slv180axxxaaaaahaain
[Model] slv180axxxaaaaahaain
Model_type Input
Polarity   Non-Inverting
Enable   Active-High
Vinl =  0.800V
Vinh =  1.000V
C_comp   2.000pF   1.500pF   2.500pF
[Temperature Range]   25.000   0.125k   -40.000
[Voltage Range]   1.800V   1.750V   1.850V
[C Comp Corner]
C_comp   2.000pF   1.500pF   2.500pF
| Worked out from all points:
|   GND clamp passes 1 mA (typ) near -0.49 V on its own axis
|   POWER clamp passes 1 mA (typ) near -0.42 V on its own axis
[GND_clamp]
|Voltage   I(typ)   I(min)   I(max)
-1.8V     -570.9mA   -571.8mA   -572.8mA
-1.097V   -67.51mA   -81.62mA   -63.29mA
-1.06V    -53.41mA   -65.4mA    -52.07mA
-1.023V   -43.08mA   -51.93mA   -44.8mA
-986mV    -35.99mA   -41.38mA   -39.76mA
-949mV    -31.01mA   -33.53mA   -35.66mA
-912mV    -27.14mA   -27.8mA    -31.91mA
-838mV    -20.7mA    -20.03mA   -24.81mA
-616mV    -5.39mA    -5.945mA   -6.501mA
-468mV    -528.6uA   -1.119mA   -493.8uA
-283mV    -1.801uA   -19.55uA   -455.8nA
1.8V      0A         0A         0A
[POWER_clamp]
|Voltage   I(typ)   I(min)   I(max)
-1.789V   617.6mA    624.8mA    616mA
-1.086V   74.33mA    97.45mA    62.64mA
-1.049V   55.89mA    77.46mA    46.64mA
-1.012V   41.21mA    59.84mA    35.93mA
-975mV    30.78mA    45.07mA    29.76mA
-938mV    24.15mA    33.5mA     26.13mA
-901mV    20.08mA    25.08mA    23.53mA
-827mV    15.25mA    15.43mA    19.16mA
-679mV    8.594mA    7.667mA    11.28mA
-420mV    968.7uA    1.245mA    1.301mA
-272mV    22.7uA     105.6uA    13.93uA
1.8V      0A         0A         0A
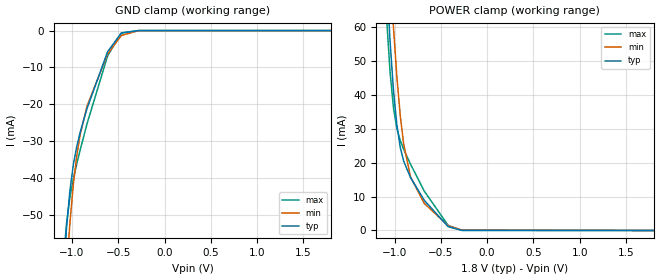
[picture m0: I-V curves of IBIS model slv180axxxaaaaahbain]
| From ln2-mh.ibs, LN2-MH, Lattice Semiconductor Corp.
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|   Model slv180axxxaaaaahbain
[Model] slv180axxxaaaaahbain
Model_type Input
Polarity   Non-Inverting
Enable   Active-High
Vinl =  0.800V
Vinh =  1.000V
C_comp   2.000pF   1.500pF   2.500pF
[Temperature Range]   25.000   0.125k   -40.000
[Voltage Range]   1.800V   1.750V   1.850V
[C Comp Corner]
C_comp   2.000pF   1.500pF   2.500pF
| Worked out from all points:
|   GND clamp passes 1 mA (typ) near -0.48 V on its own axis
|   POWER clamp passes 1 mA (typ) near -0.41 V on its own axis
[GND_clamp]
|Voltage   I(typ)   I(min)   I(max)
-1.8V     -570.9mA   -571.9mA   -572.9mA
-1.097V   -67.81mA   -81.9mA    -63.67mA
-1.06V    -53.77mA   -65.72mA   -52.52mA
-1.023V   -43.49mA   -52.29mA   -45.29mA
-986mV    -36.44mA   -41.78mA   -40.28mA
-949mV    -31.48mA   -33.97mA   -36.18mA
-912mV    -27.61mA   -28.25mA   -32.43mA
-838mV    -21.16mA   -20.5mA    -25.31mA
-616mV    -5.752mA   -6.337mA   -6.893mA
-468mV    -672.3uA   -1.34mA    -632.2uA
-283mV    -2.566uA   -29.6uA    -635.3nA
1.8V      0A         0A         0A
[POWER_clamp]
|Voltage   I(typ)   I(min)   I(max)
-1.789V   617.6mA    624.9mA    616.1mA
-1.086V   74.52mA    97.65mA    62.85mA
-1.049V   56.11mA    77.68mA    46.92mA
-1.012V   41.47mA    60.08mA    36.26mA
-975mV    31.09mA    45.35mA    30.13mA
-938mV    24.49mA    33.81mA    26.52mA
-901mV    20.43mA    25.41mA    23.92mA
-827mV    15.59mA    15.78mA    19.54mA
-679mV    8.904mA    7.985mA    11.62mA
-420mV    1.1mA      1.396mA    1.463mA
-272mV    30.38uA    133.6uA    19.74uA
1.8V      0A         0A         0A
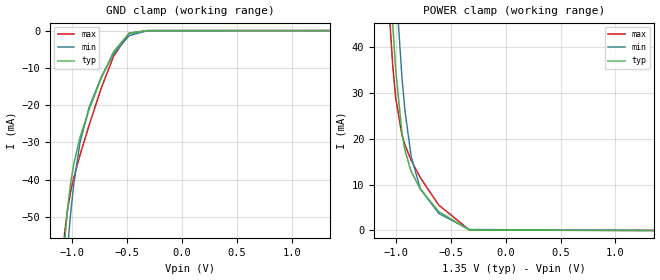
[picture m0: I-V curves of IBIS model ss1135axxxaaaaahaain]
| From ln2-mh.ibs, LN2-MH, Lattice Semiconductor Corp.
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|   Model ss1135axxxaaaaahaain
[Model] ss1135axxxaaaaahaain
Model_type Input
Polarity   Non-Inverting
Enable   Active-High
Vinl =  0.575V
Vinh =  0.775V
C_comp   2.000pF   1.500pF   2.500pF
[Temperature Range]   25.000   0.125k   -40.000
[Voltage Range]   1.350V   1.310V   1.390V
[C Comp Corner]
C_comp   2.000pF   1.500pF   2.500pF
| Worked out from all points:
|   GND clamp passes 1 mA (typ) near -0.50 V on its own axis
|   POWER clamp passes 1 mA (typ) near -0.45 V on its own axis
[GND_clamp]
|Voltage   I(typ)   I(min)   I(max)
-1.35V    -224.6mA   -236.1mA   -220mA
-1.07V    -56.72mA   -69.44mA   -54.48mA
-1.042V   -47.78mA   -58.39mA   -47.95mA
-1.014V   -40.95mA   -48.99mA   -43.23mA
-986mV    -35.83mA   -41.27mA   -39.56mA
-930mV    -28.77mA   -30.24mA   -33.52mA
-846mV    -21.21mA   -20.61mA   -25.4mA
-734mV    -12.66mA   -12.39mA   -15.33mA
-622mV    -5.646mA   -6.175mA   -6.812mA
-482mV    -724.7uA   -1.376mA   -718.8uA
-314mV    -4.112uA   -39.82uA   -1.108uA
1.35V     0A         0A         0A
[POWER_clamp]
|Voltage   I(typ)   I(min)   I(max)
-1.338V   248.4mA    267.8mA    238.2mA
-1.086V   72.51mA    96.3mA     59.72mA
-1.058V   57.87mA    80.81mA    46.49mA
-1.03V    45.21mA    66.58mA    36.13mA
-1.002V   34.88mA    53.83mA    28.8mA
-946mV    21.35mA    33.5mA     20.88mA
-918mV    17.48mA    26.1mA     18.64mA
-862mV    12.87mA    16.19mA    15.31mA
-778mV    9.037mA    9.084mA    11.51mA
-610mV    4.102mA    3.705mA    5.539mA
-330mV    85.19uA    208uA      91.66uA
1.35V     0A         0A         0A
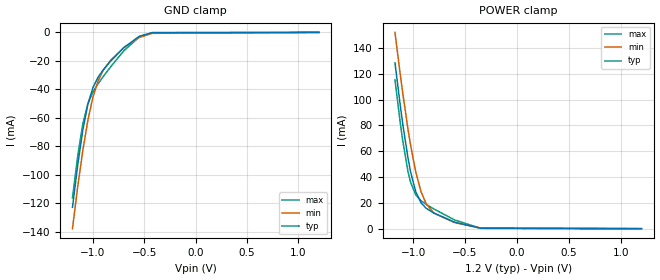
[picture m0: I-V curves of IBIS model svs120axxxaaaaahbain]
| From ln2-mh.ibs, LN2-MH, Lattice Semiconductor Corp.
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|   Model svs120axxxaaaaahbain
[Model] svs120axxxaaaaahbain
Model_type Input
Polarity   Non-Inverting
Enable   Active-High
Vinl =  0.0V
Vinh =  0.400V
C_comp   2.000pF   1.500pF   2.500pF
[Temperature Range]   25.000   0.125k   -40.000
[Voltage Range]   1.200V   1.160V   1.240V
[C Comp Corner]
C_comp   2.000pF   1.500pF   2.500pF
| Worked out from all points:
|   GND clamp passes 1 mA (typ) near -0.49 V on its own axis
|   POWER clamp passes 1 mA (typ) near -0.42 V on its own axis
[GND_clamp]
|Voltage   I(typ)   I(min)   I(max)
-1.2V     -122.9mA   -137.9mA   -116.3mA
-1.15V    -93.72mA   -109mA     -87.35mA
-1.1V     -68.98mA   -83.21mA   -64.57mA
-1.05V    -50.44mA   -61.68mA   -50mA
-1V       -38.59mA   -45.27mA   -41.75mA
-950mV    -31.38mA   -33.98mA   -36.03mA
-900mV    -26.28mA   -26.56mA   -31.01mA
-825mV    -19.94mA   -19.27mA   -23.89mA
-700mV    -10.71mA   -10.73mA   -12.93mA
-550mV    -2.746mA   -3.562mA   -3.157mA
-425mV    -221.5uA   -657.6uA   -155.4uA
1.2V      0A         0A         0A
[POWER_clamp]
|Voltage   I(typ)   I(min)   I(max)
-1.175V   128.6mA    152.2mA    115.4mA
-1.125V   96.07mA    120.1mA    82.67mA
-1.1V     81.1mA     105mA      68.1mA
-1.05V    54.92mA    77.25mA    44.43mA
-1.025V   44.23mA    64.91mA    36.08mA
-975mV    28.66mA    44.03mA    26.21mA
-925mV    20.16mA    28.93mA    21.69mA
-875mV    15.83mA    19.39mA    18.86mA
-800mV    12.09mA    12.05mA    15.26mA
-600mV    5.076mA    4.664mA    6.746mA
-350mV    256.2uA    490.5uA    300.9uA
1.2V      0A         0A         0A
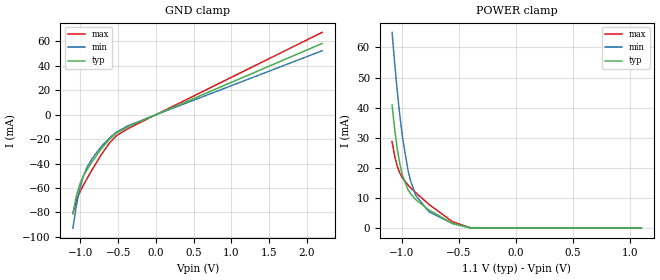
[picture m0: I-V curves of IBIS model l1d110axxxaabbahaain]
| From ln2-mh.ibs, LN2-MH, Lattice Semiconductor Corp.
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|   Model l1d110axxxaabbahaain
[Model] l1d110axxxaabbahaain
Model_type Input
Polarity   Non-Inverting
Enable   Active-High
Vinl =  0.200V
Vinh =  0.300V
C_comp   2.000pF   1.500pF   2.500pF
[Temperature Range]   25.000   0.125k   -40.000
[Voltage Range]   1.100V   1.070V   1.130V
[C Comp Corner]
C_comp   2.000pF   1.500pF   2.500pF
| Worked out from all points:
|   GND clamp passes 1 mA (typ) near -0.04 V on its own axis
|   POWER clamp passes 1 mA (typ) near -0.52 V on its own axis
[GND_clamp]
|Voltage   I(typ)   I(min)   I(max)
-1.1V     -81.27mA   -92.91mA   -80.74mA
-1.054V   -66.47mA   -74.48mA   -70.12mA
-1.008V   -56.83mA   -60.43mA   -63.29mA
-962mV    -50.37mA   -50.47mA   -57.79mA
-916mV    -45.34mA   -43.51mA   -52.66mA
-847mV    -38.71mA   -36.09mA   -45.22mA
-732mV    -28.66mA   -26.73mA   -33.43mA
-617mV    -20.17mA   -19.13mA   -23.3mA
-525mV    -15.14mA   -14.39mA   -17.3mA
-387mV    -10.47mA   -9.605mA   -12.01mA
-88mV     -2.374mA   -2.153mA   -2.729mA
2.2V      58.28mA    52.3mA     67.35mA
[POWER_clamp]
|Voltage   I(typ)   I(min)   I(max)
-1.085V   40.89mA    65.02mA    28.76mA
-1.062V   32.71mA    54.6mA     23.82mA
-1.039V   26.14mA    45.23mA    20.45mA
-1.016V   21.11mA    37mA       18.19mA
-993mV    17.43mA    29.99mA    16.6mA
-947mV    12.89mA    19.52mA    14.37mA
-924mV    11.49mA    15.87mA    13.47mA
-878mV    9.492mA    10.92mA    11.79mA
-763mV    6.063mA    5.459mA    7.912mA
-556mV    1.572mA    1.535mA    2.157mA
-395mV    15.13uA    142.3uA    35.24uA
1.1V      0A         0A         0A
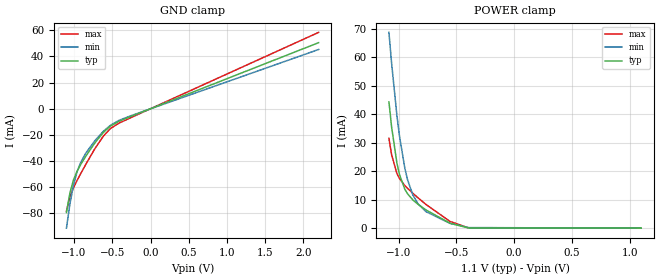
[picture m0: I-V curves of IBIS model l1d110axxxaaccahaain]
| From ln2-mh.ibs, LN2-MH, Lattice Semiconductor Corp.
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|   Model l1d110axxxaaccahaain
[Model] l1d110axxxaaccahaain
Model_type Input
Polarity   Non-Inverting
Enable   Active-High
Vinl =  0.200V
Vinh =  0.300V
C_comp   2.000pF   1.500pF   2.500pF
[Temperature Range]   25.000   0.125k   -40.000
[Voltage Range]   1.100V   1.070V   1.130V
[C Comp Corner]
C_comp   2.000pF   1.500pF   2.500pF
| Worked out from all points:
|   GND clamp passes 1 mA (typ) near -0.04 V on its own axis
|   POWER clamp passes 1 mA (typ) near -0.51 V on its own axis
[GND_clamp]
|Voltage   I(typ)   I(min)   I(max)
-1.1V     -79.59mA   -91.56mA   -78.52mA
-1.054V   -64.49mA   -72.94mA   -67.58mA
-1.008V   -54.64mA   -58.69mA   -60.65mA
-962mV    -48.11mA   -48.58mA   -55.17mA
-916mV    -43.08mA   -41.55mA   -50.09mA
-847mV    -36.51mA   -34.13mA   -42.73mA
-732mV    -26.58mA   -24.86mA   -31.08mA
-617mV    -18.22mA   -17.39mA   -21.08mA
-525mV    -13.35mA   -12.81mA   -15.26mA
-410mV    -9.655mA   -8.938mA   -11.06mA
-249mV    -5.83mA    -5.289mA   -6.701mA
2.2V      50.54mA    45.32mA    58.42mA
[POWER_clamp]
|Voltage   I(typ)   I(min)   I(max)
-1.085V   44.29mA    68.67mA    31.51mA
-1.062V   35.54mA    57.9mA     25.79mA
-1.016V   22.84mA    39.56mA    19.17mA
-993mV    18.72mA    32.16mA    17.34mA
-947mV    13.63mA    20.97mA    14.91mA
-924mV    12.07mA    17.02mA    13.96mA
-878mV    9.916mA    11.64mA    12.23mA
-832mV    8.338mA    8.48mA     10.6mA
-763mV    6.356mA    5.767mA    8.274mA
-556mV    1.724mA    1.672mA    2.36mA
-395mV    56.01uA    193.2uA    81.38uA
1.1V      0A         0A         0A
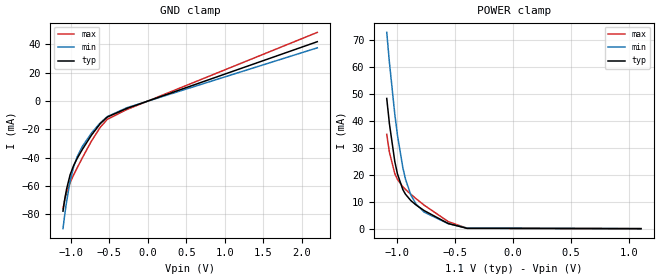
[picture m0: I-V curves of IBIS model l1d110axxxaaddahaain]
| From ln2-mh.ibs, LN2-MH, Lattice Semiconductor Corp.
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|   Model l1d110axxxaaddahaain
[Model] l1d110axxxaaddahaain
Model_type Input
Polarity   Non-Inverting
Enable   Active-High
Vinl =  0.200V
Vinh =  0.300V
C_comp   2.000pF   1.500pF   2.500pF
[Temperature Range]   25.000   0.125k   -40.000
[Voltage Range]   1.100V   1.070V   1.130V
[C Comp Corner]
C_comp   2.000pF   1.500pF   2.500pF
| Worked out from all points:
|   GND clamp passes 1 mA (typ) near -0.05 V on its own axis
|   POWER clamp passes 1 mA (typ) near -0.50 V on its own axis
[GND_clamp]
|Voltage   I(typ)   I(min)   I(max)
-1.1V     -77.68mA   -90.03mA   -76mA
-1.077V   -69.22mA   -80.09mA   -69.59mA
-1.054V   -62.22mA   -71.19mA   -64.67mA
-1.008V   -52.13mA   -56.72mA   -57.63mA
-962mV    -45.52mA   -46.44mA   -52.18mA
-916mV    -40.5mA    -39.32mA   -47.17mA
-847mV    -34.01mA   -31.91mA   -39.91mA
-732mV    -24.21mA   -22.75mA   -28.41mA
-617mV    -16.02mA   -15.44mA   -18.58mA
-525mV    -11.33mA   -11.02mA   -12.94mA
-272mV    -5.266mA   -4.782mA   -6.058mA
2.2V      41.78mA    37.47mA    48.35mA
[POWER_clamp]
|Voltage   I(typ)   I(min)   I(max)
-1.085V   48.34mA    72.86mA    35.01mA
-1.062V   38.96mA    61.73mA    28.37mA
-1.016V   24.99mA    42.56mA    20.46mA
-993mV    20.33mA    34.72mA    18.3mA
-947mV    14.53mA    22.7mA     15.57mA
-924mV    12.78mA    18.4mA     14.56mA
-878mV    10.42mA    12.51mA    12.76mA
-832mV    8.748mA    9.049mA    11.09mA
-763mV    6.694mA    6.125mA    8.705mA
-556mV    1.9mA      1.829mA    2.606mA
-395mV    105uA      252.7uA    142.4uA
1.1V      0A         0A         0A
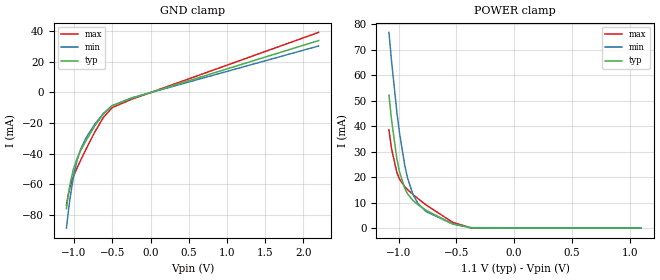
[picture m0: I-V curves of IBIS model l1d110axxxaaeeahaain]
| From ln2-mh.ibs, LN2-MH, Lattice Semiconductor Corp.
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|   Model l1d110axxxaaeeahaain
[Model] l1d110axxxaaeeahaain
Model_type Input
Polarity   Non-Inverting
Enable   Active-High
Vinl =  0.200V
Vinh =  0.300V
C_comp   2.000pF   1.500pF   2.500pF
[Temperature Range]   25.000   0.125k   -40.000
[Voltage Range]   1.100V   1.070V   1.130V
[C Comp Corner]
C_comp   2.000pF   1.500pF   2.500pF
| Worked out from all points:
|   GND clamp passes 1 mA (typ) near -0.06 V on its own axis
|   POWER clamp passes 1 mA (typ) near -0.49 V on its own axis
[GND_clamp]
|Voltage   I(typ)   I(min)   I(max)
-1.1V     -75.94mA   -88.64mA   -73.7mA
-1.077V   -67.32mA   -78.6mA    -67.06mA
-1.054V   -60.17mA   -69.6mA    -61.99mA
-1.008V   -49.86mA   -54.92mA   -54.85mA
-962mV    -43.18mA   -44.5mA    -49.45mA
-916mV    -38.19mA   -37.32mA   -44.53mA
-847mV    -31.78mA   -29.91mA   -37.39mA
-732mV    -22.11mA   -20.87mA   -26.04mA
-617mV    -14.06mA   -13.69mA   -16.35mA
-502mV    -8.709mA   -8.582mA   -9.912mA
-249mV    -3.916mA   -3.552mA   -4.505mA
2.2V      33.93mA    30.39mA    39.27mA
[POWER_clamp]
|Voltage   I(typ)   I(min)   I(max)
-1.085V   52.16mA    76.73mA    38.51mA
-1.062V   42.24mA    65.28mA    31.02mA
-1.016V   27.1mA     45.38mA    21.77mA
-993mV    21.93mA    37.14mA    19.24mA
-947mV    15.42mA    24.36mA    16.17mA
-924mV    13.47mA    19.73mA    15.09mA
-878mV    10.89mA    13.34mA    13.23mA
-832mV    9.125mA    9.591mA    11.52mA
-763mV    7.003mA    6.459mA    9.086mA
-533mV    1.661mA    1.646mA    2.285mA
-372mV    62.23uA    195.1uA    78.98uA
1.1V      0A         0A         0A
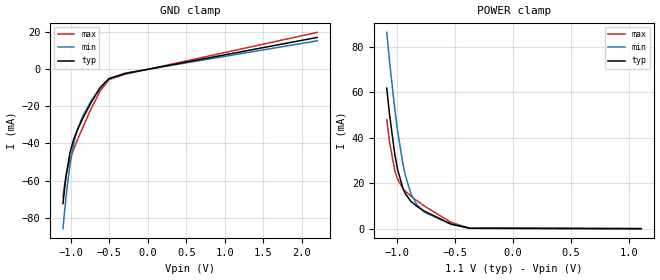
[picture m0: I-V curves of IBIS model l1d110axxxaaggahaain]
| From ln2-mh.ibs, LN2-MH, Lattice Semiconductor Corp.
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|   Model l1d110axxxaaggahaain
[Model] l1d110axxxaaggahaain
Model_type Input
Polarity   Non-Inverting
Enable   Active-High
Vinl =  0.200V
Vinh =  0.300V
C_comp   2.000pF   1.500pF   2.500pF
[Temperature Range]   25.000   0.125k   -40.000
[Voltage Range]   1.100V   1.070V   1.130V
[C Comp Corner]
C_comp   2.000pF   1.500pF   2.500pF
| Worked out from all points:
|   GND clamp passes 1 mA (typ) near -0.13 V on its own axis
|   POWER clamp passes 1 mA (typ) near -0.47 V on its own axis
[GND_clamp]
|Voltage   I(typ)   I(min)   I(max)
-1.1V     -72.32mA   -85.87mA   -68.86mA
-1.077V   -63.28mA   -75.58mA   -61.64mA
-1.054V   -55.72mA   -66.31mA   -56.11mA
-1.008V   -44.76mA   -51.09mA   -48.54mA
-962mV    -37.84mA   -40.24mA   -43.15mA
-916mV    -32.89mA   -32.84mA   -38.42mA
-847mV    -26.78mA   -25.47mA   -31.71mA
-732mV    -17.64mA   -16.83mA   -20.99mA
-617mV    -9.887mA   -9.991mA   -11.62mA
-502mV    -4.966mA   -5.276mA   -5.61mA
-295mV    -2.343mA   -2.141mA   -2.698mA
2.2V      17.12mA    15.32mA    19.84mA
[POWER_clamp]
|Voltage   I(typ)   I(min)   I(max)
-1.085V   61.79mA    86.32mA    47.89mA
-1.062V   50.64mA    74.13mA    38.42mA
-1.016V   32.78mA    52.55mA    25.61mA
-993mV    26.31mA    43.38mA    21.92mA
-947mV    17.84mA    28.73mA    17.73mA
-924mV    15.28mA    23.25mA    16.42mA
-878mV    12.05mA    15.53mA    14.35mA
-832mV    10.02mA    10.97mA    12.54mA
-763mV    7.725mA    7.27mA     9.989mA
-533mV    2.011mA    1.955mA    2.772mA
-372mV    150.5uA    304.4uA    188.9uA
1.1V      0A         0A         0A
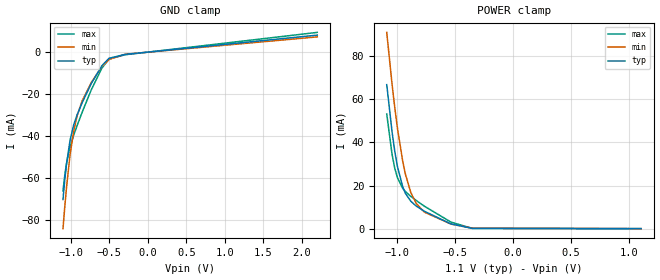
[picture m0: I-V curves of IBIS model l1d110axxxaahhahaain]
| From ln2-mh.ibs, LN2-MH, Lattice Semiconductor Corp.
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|   Model l1d110axxxaahhahaain
[Model] l1d110axxxaahhahaain
Model_type Input
Polarity   Non-Inverting
Enable   Active-High
Vinl =  0.200V
Vinh =  0.300V
C_comp   2.000pF   1.500pF   2.500pF
[Temperature Range]   25.000   0.125k   -40.000
[Voltage Range]   1.100V   1.070V   1.130V
[C Comp Corner]
C_comp   2.000pF   1.500pF   2.500pF
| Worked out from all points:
|   GND clamp passes 1 mA (typ) near -0.27 V on its own axis
|   POWER clamp passes 1 mA (typ) near -0.46 V on its own axis
[GND_clamp]
|Voltage   I(typ)   I(min)   I(max)
-1.1V     -70.35mA   -84.29mA   -66.34mA
-1.077V   -61.11mA   -73.88mA   -58.82mA
-1.054V   -53.33mA   -64.47mA   -53.04mA
-1.008V   -42.02mA   -48.98mA   -45.19mA
-962mV    -34.9mA    -37.89mA   -39.73mA
-916mV    -29.89mA   -30.34mA   -35mA
-847mV    -23.81mA   -22.91mA   -28.32mA
-732mV    -14.96mA   -14.43mA   -17.93mA
-594mV    -6.432mA   -6.889mA   -7.58mA
-502mV    -2.956mA   -3.505mA   -3.302mA
-295mV    -1.108mA   -1.028mA   -1.278mA
2.2V      8.093mA    7.263mA    9.402mA
[POWER_clamp]
|Voltage   I(typ)   I(min)   I(max)
-1.085V   66.78mA    91.02mA    53.14mA
-1.039V   44.73mA    66.84mA    34.34mA
-1.016V   35.93mA    56.16mA    28.03mA
-993mV    28.79mA    46.57mA    23.62mA
-947mV    19.24mA    31.02mA    18.64mA
-924mV    16.33mA    25.13mA    17.17mA
-878mV    12.7mA     16.72mA    14.95mA
-832mV    10.5mA     11.72mA    13.08mA
-763mV    8.103mA    7.701mA    10.47mA
-533mV    2.197mA    2.117mA    3.035mA
-349mV    107.2uA    245.1uA    126.2uA
1.1V      0A         0A         0A
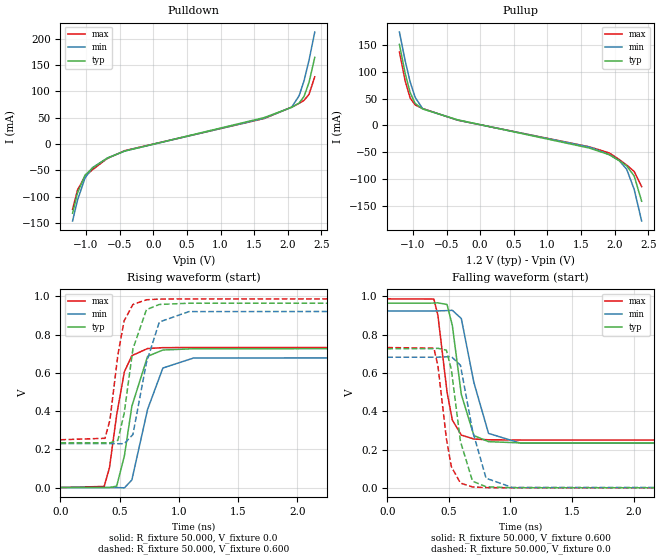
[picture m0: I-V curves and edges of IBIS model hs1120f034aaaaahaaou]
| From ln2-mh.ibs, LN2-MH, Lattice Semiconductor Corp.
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|   Model hs1120f034aaaaahaaou
[Model] hs1120f034aaaaahaaou
Model_type Output
Polarity   Non-Inverting
Enable   Active-High
Vmeas =  0.600V
Cref =  20.000pF
Rref =  50.000
Vref =  0.600V
C_comp   2.000pF   1.500pF   2.500pF
[Temperature Range]   25.000   0.125k   -40.000
[Voltage Range]   1.200V   1.160V   1.240V
[C Comp Corner]
C_comp   2.000pF   1.500pF   2.500pF
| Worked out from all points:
|   slope of the pulldown table from 0 to 0.18 V, typ, clamps not added: 31.9 ohm
|   slope of the pullup table from 0 to 0.18 V, typ, clamps not added: 32.3 ohm
|   rising waveform, R_fixture 50.000, V_fixture 0.0: 20-80 % time 119ps typ, 146ps min, 107ps max; typ from 0 V to 0.727 V
|   rising waveform, R_fixture 50.000, V_fixture 0.600: 20-80 % time 106ps typ, 127ps min, 97.7ps max; typ from 0.234 V to 0.965 V
|   falling waveform, R_fixture 50.000, V_fixture 0.600: 20-80 % time 96.2ps typ, 123ps min, 88ps max; typ from 0.965 V to 0.234 V
|   falling waveform, R_fixture 50.000, V_fixture 0.0: 20-80 % time 92.7ps typ, 117ps min, 85.6ps max; typ from 0.727 V to 0 V
[Pulldown]
|Voltage   I(typ)   I(min)   I(max)
-1.2V     -131.7mA   -146.5mA   -124.4mA
-1.126V   -92.86mA   -106.7mA   -87.32mA
-1.015V   -59.28mA   -64.7mA    -61.33mA
-904mV    -45.76mA   -45.03mA   -48.92mA
-682mV    -26.87mA   -26.53mA   -27.43mA
-423mV    -13.33mA   -13.31mA   -12.57mA
1.649V    50.26mA    48.96mA    48.52mA
2.056V    69.68mA    69.95mA    70.1mA
2.167V    77.91mA    91.66mA    77.34mA
2.241V    90.47mA    120.4mA    83.09mA
2.315V    117.4mA    159.6mA    94.54mA
2.4V      164.7mA    213mA      127.8mA
[Pullup]
|Voltage   I(typ)   I(min)   I(max)
-1.2V     151mA      174.1mA    137mA
-1.115V   97.23mA    120.7mA    83.1mA
-1.041V   61.27mA    81.31mA    51.23mA
-967mV    40.99mA    52.5mA     38.23mA
-856mV    30.65mA    31.29mA    31.46mA
-338mV    10.53mA    9.896mA    9.839mA
1.623V    -42.27mA   -40.38mA   -39.95mA
1.919V    -54.7mA    -54.35mA   -51.34mA
2.067V    -65.74mA   -65.68mA   -63.64mA
2.178V    -75.57mA   -81.91mA   -74.02mA
2.289V    -94.3mA    -119.2mA   -85.9mA
2.4V      -141.4mA   -178.3mA   -114.3mA
[Ramp]
| variable   typ   min   max
dV/dt_r   0.436/0.119n   0.409/0.146n   0.440/0.107n
dV/dt_f   0.439/0.103n   0.421/0.136n   0.444/91.393p
R_load = 50.000
[Rising Waveform]
R_fixture= 50.000
V_fixture= 0.0
V_fixture_min= 0.0
V_fixture_max= 0.0
|time   V(typ)   V(min)   V(max)
0s        1.029uV    5.623uV    470.9nV
369ps     60.18uV    42.1uV     5.509mV
414ps     -551.1uV   69.3uV     103.7mV
475ps     7.496mV    -357.6uV   381.2mV
540ps     165.4mV    -1.821mV   605.5mV
603ps     425.1mV    39.28mV    689.8mV
736ps     686.3mV    409mV      727.1mV
865ps     719.3mV    625.1mV    731.6mV
1.125ns   726mV      677.6mV    732.5mV
10ns      726.5mV    682.1mV    732.6mV
[Rising Waveform]
R_fixture= 50.000
V_fixture= 0.600
V_fixture_min= 0.583
V_fixture_max= 0.619
|time   V(typ)   V(min)   V(max)
0s        233.9mV    229.5mV    249.7mV
376ps     233.9mV    229.6mV    257.4mV
418ps     233.5mV    229.6mV    352.9mV
485ps     246.7mV    229.1mV    694.3mV
538ps     387.6mV    229mV      872.4mV
612ps     724.5mV    277.2mV    957.5mV
726ps     930.3mV    653.1mV    982.2mV
835ps     957.6mV    866mV      985.8mV
1.085ns   964.1mV    920.3mV    986.8mV
10ns      964.5mV    923.8mV    986.9mV
[Falling Waveform]
R_fixture= 50.000
V_fixture= 0.600
V_fixture_min= 0.583
V_fixture_max= 0.619
|time   V(typ)   V(min)   V(max)
0s        964.5mV    923.8mV    986.9mV
378ps     964.8mV    923.9mV    986.1mV
411ps     966.3mV    924mV      900.2mV
485ps     957.3mV    925.6mV    500.5mV
528ps     848.2mV    927.3mV    353.9mV
601ps     488mV      884mV      275.7mV
703ps     273.1mV    550.1mV    255mV
822ps     241.2mV    284.3mV    251mV
1.082ns   234.7mV    233.3mV    249.8mV
10ns      233.9mV    229.5mV    249.7mV
[Falling Waveform]
R_fixture= 50.000
V_fixture= 0.0
V_fixture_min= 0.0
V_fixture_max= 0.0
|time   V(typ)   V(min)   V(max)
0s        726.5mV    682.1mV    732.6mV
378ps     727.1mV    682.1mV    729.8mV
411ps     728.8mV    682.4mV    637.4mV
480ps     718.8mV    684.3mV    256.5mV
520ps     617.9mV    685.5mV    110.6mV
594ps     242mV      640.3mV    24.9mV
692ps     34.95mV    298.9mV    4.718mV
802ps     5.731mV    50.25mV    1.064mV
1.012ns   584.3uV    2.559mV    154.2uV
10ns      1.042uV    5.627uV    488.1nV
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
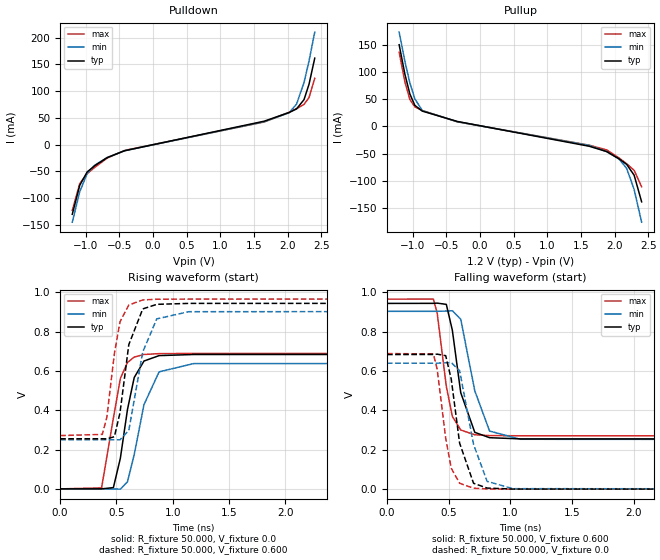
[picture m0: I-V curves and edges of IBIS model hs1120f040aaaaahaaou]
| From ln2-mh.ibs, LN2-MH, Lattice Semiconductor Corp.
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|   Model hs1120f040aaaaahaaou
[Model] hs1120f040aaaaahaaou
Model_type Output
Polarity   Non-Inverting
Enable   Active-High
Vmeas =  0.600V
Cref =  20.000pF
Rref =  50.000
Vref =  0.600V
C_comp   2.000pF   1.500pF   2.500pF
[Temperature Range]   25.000   0.125k   -40.000
[Voltage Range]   1.200V   1.160V   1.240V
[C Comp Corner]
C_comp   2.000pF   1.500pF   2.500pF
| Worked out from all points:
|   slope of the pulldown table from 0 to 0.18 V, typ, clamps not added: 36.9 ohm
|   slope of the pullup table from 0 to 0.18 V, typ, clamps not added: 37.3 ohm
|   rising waveform, R_fixture 50.000, V_fixture 0.0: 20-80 % time 118ps typ, 146ps min, 109ps max; typ from 0 V to 0.684 V
|   rising waveform, R_fixture 50.000, V_fixture 0.600: 20-80 % time 102ps typ, 124ps min, 96.4ps max; typ from 0.255 V to 0.943 V
|   falling waveform, R_fixture 50.000, V_fixture 0.600: 20-80 % time 98.5ps typ, 126ps min, 90.9ps max; typ from 0.943 V to 0.255 V
|   falling waveform, R_fixture 50.000, V_fixture 0.0: 20-80 % time 95.1ps typ, 119ps min, 89.2ps max; typ from 0.684 V to 0 V
[Pulldown]
|Voltage   I(typ)   I(min)   I(max)
-1.2V     -130.4mA   -145.2mA   -123.2mA
-1.089V   -76.06mA   -88.24mA   -72.96mA
-978mV    -51.12mA   -53.82mA   -54.4mA
-867mV    -39.66mA   -38.57mA   -42.73mA
-682mV    -24.46mA   -24.18mA   -25.24mA
-423mV    -11.56mA   -11.59mA   -10.92mA
1.649V    43.64mA    42.58mA    42.18mA
2.019V    59.89mA    59.32mA    60.3mA
2.13V     66.73mA    75.74mA    67.04mA
2.241V    84.04mA    116.1mA    75.18mA
2.315V    112.8mA    156.3mA    87.92mA
2.4V      161.6mA    210.3mA    123.8mA
[Pullup]
|Voltage   I(typ)   I(min)   I(max)
-1.2V     150mA      173.2mA    136.2mA
-1.115V   95.98mA    119.5mA    81.92mA
-1.041V   59.5mA     79.86mA    49.41mA
-967mV    38.64mA    50.65mA    35.94mA
-856mV    28.09mA    28.99mA    29.17mA
-338mV    9.116mA    8.575mA    8.54mA
1.623V    -36.48mA   -34.93mA   -34.51mA
1.882V    -46.27mA   -46.35mA   -43.16mA
2.067V    -59.74mA   -60.16mA   -58.07mA
2.178V    -69.72mA   -77.16mA   -68.49mA
2.289V    -89.63mA   -115.9mA   -80.62mA
2.4V      -138.5mA   -175.9mA   -110.9mA
[Ramp]
| variable   typ   min   max
dV/dt_r   0.410/0.118n   0.384/0.146n   0.413/0.109n
dV/dt_f   0.414/0.106n   0.397/0.140n   0.418/93.486p
R_load = 50.000
[Rising Waveform]
R_fixture= 50.000
V_fixture= 0.0
V_fixture_min= 0.0
V_fixture_max= 0.0
|time   V(typ)   V(min)   V(max)
0s        1.143uV    6.223uV    521.7nV
368ps     63.62uV    46.69uV    4.902mV
473ps     6.489mV    -305.6uV   359.5mV
535ps     155.9mV    -1.474mV   561.1mV
598ps     402.9mV    35.89mV    642.5mV
658ps     566.1mV    174.1mV    670.3mV
745ps     650.2mV    428.5mV    683.4mV
879ps     677.6mV    595mV      687.7mV
1.185ns   683.3mV    637mV      688.6mV
10ns      683.6mV    639.6mV    688.7mV
[Rising Waveform]
R_fixture= 50.000
V_fixture= 0.600
V_fixture_min= 0.583
V_fixture_max= 0.619
|time   V(typ)   V(min)   V(max)
0s        254.7mV    249.8mV    271mV
374ps     254.8mV    249.9mV    276.9mV
415ps     254.3mV    249.9mV    364mV
482ps     265.2mV    249.5mV    688.6mV
532ps     387.9mV    249.6mV    849.9mV
610ps     733.5mV    297.4mV    935mV
734ps     915.1mV    696.6mV    960.7mV
859ps     938.4mV    864.6mV    964.3mV
1.144ns   943.2mV    901mV      965.1mV
10ns      943.4mV    903.1mV    965.2mV
[Falling Waveform]
R_fixture= 50.000
V_fixture= 0.600
V_fixture_min= 0.583
V_fixture_max= 0.619
|time   V(typ)   V(min)   V(max)
0s        943.4mV    903.1mV    965.1mV
376ps     943.7mV    903.1mV    965.5mV
407ps     944.9mV    903.2mV    893.9mV
481ps     938.6mV    904.7mV    522.4mV
530ps     807mV      906.3mV    369.5mV
598ps     490mV      863.2mV    300.5mV
712ps     288.6mV    499.5mV    276.2mV
832ps     261.4mV    295.1mV    272.2mV
1.082ns   255.4mV    253.4mV    271.1mV
10ns      254.7mV    249.8mV    271mV
[Falling Waveform]
R_fixture= 50.000
V_fixture= 0.0
V_fixture_min= 0.0
V_fixture_max= 0.0
|time   V(typ)   V(min)   V(max)
0s        683.6mV    639.6mV    688.7mV
376ps     684.2mV    639.7mV    686.9mV
407ps     685.7mV    639.9mV    608.7mV
476ps     678mV      641.7mV    258.8mV
521ps     559mV      642.8mV    106.6mV
589ps     233.7mV    601.8mV    29.96mV
702ps     29.87mV    227.3mV    4.782mV
812ps     5.559mV    39.65mV    1.087mV
1.022ns   549.5uV    2.477mV    144.4uV
10ns      1.158uV    6.231uV    540nV
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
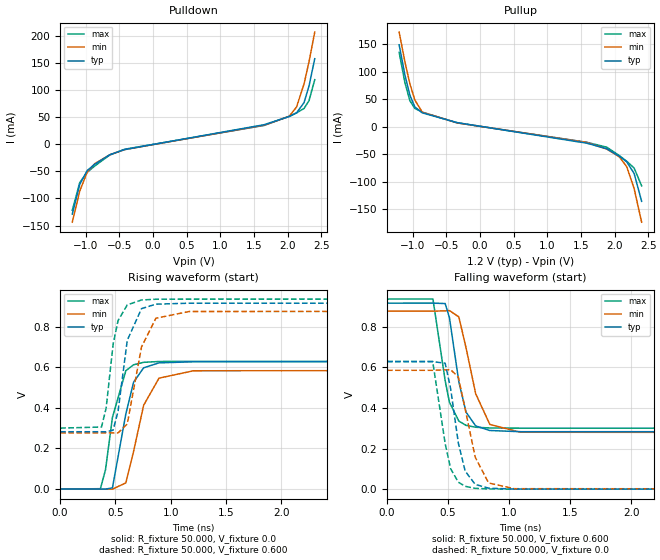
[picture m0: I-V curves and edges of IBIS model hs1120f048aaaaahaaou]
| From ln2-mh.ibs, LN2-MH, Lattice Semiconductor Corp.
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|   Model hs1120f048aaaaahaaou
[Model] hs1120f048aaaaahaaou
Model_type Output
Polarity   Non-Inverting
Enable   Active-High
Vmeas =  0.600V
Cref =  20.000pF
Rref =  50.000
Vref =  0.600V
C_comp   2.000pF   1.500pF   2.500pF
[Temperature Range]   25.000   0.125k   -40.000
[Voltage Range]   1.200V   1.160V   1.240V
[C Comp Corner]
C_comp   2.000pF   1.500pF   2.500pF
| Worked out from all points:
|   slope of the pulldown table from 0 to 0.18 V, typ, clamps not added: 44.5 ohm
|   slope of the pullup table from 0 to 0.18 V, typ, clamps not added: 44.9 ohm
|   rising waveform, R_fixture 50.000, V_fixture 0.0: 20-80 % time 121ps typ, 153ps min, 108ps max; typ from 0 V to 0.627 V
|   rising waveform, R_fixture 50.000, V_fixture 0.600: 20-80 % time 101ps typ, 127ps min, 90.8ps max; typ from 0.282 V to 0.916 V
|   falling waveform, R_fixture 50.000, V_fixture 0.600: 20-80 % time 105ps typ, 136ps min, 94.6ps max; typ from 0.916 V to 0.282 V
|   falling waveform, R_fixture 50.000, V_fixture 0.0: 20-80 % time 101ps typ, 126ps min, 93.5ps max; typ from 0.627 V to 0 V
[Pulldown]
|Voltage   I(typ)   I(min)   I(max)
-1.2V     -128.9mA   -143.8mA   -121.8mA
-1.089V   -73.85mA   -86.32mA   -70.61mA
-978mV    -48.21mA   -51.24mA   -51.6mA
-867mV    -36.76mA   -35.77mA   -40.02mA
-645mV    -19.29mA   -19.32mA   -19.79mA
-423mV    -9.615mA   -9.692mA   -9.044mA
1.649V    36.31mA    35.55mA    34.98mA
2.019V    51.34mA    51.54mA    51.84mA
2.13V     58.1mA     69.13mA    58.18mA
2.241V    77.15mA    111.6mA    66.35mA
2.315V    107.9mA    152.7mA    80.79mA
2.4V      158.2mA    207.4mA    119.5mA
[Pullup]
|Voltage   I(typ)   I(min)   I(max)
-1.2V     149.1mA    172.2mA    135.3mA
-1.115V   94.65mA    118.3mA    80.64mA
-1.041V   57.63mA    78.35mA    47.41mA
-967mV    36.14mA    48.7mA     33.41mA
-856mV    25.33mA    26.57mA    26.62mA
-338mV    7.596mA    7.177mA    7.095mA
1.586V    -29.78mA   -28.41mA   -28.15mA
1.882V    -39.92mA   -40.44mA   -37.1mA
2.067V    -53.43mA   -54.43mA   -52.11mA
2.178V    -63.6mA    -72.3mA    -62.57mA
2.289V    -84.85mA   -112.4mA   -75.03mA
2.4V      -135.5mA   -173.4mA   -107.4mA
[Ramp]
| variable   typ   min   max
dV/dt_r   0.376/0.121n   0.351/0.153n   0.378/0.108n
dV/dt_f   0.380/0.113n   0.365/0.152n   0.383/95.779p
R_load = 50.000
[Rising Waveform]
R_fixture= 50.000
V_fixture= 0.0
V_fixture_min= 0.0
V_fixture_max= 0.0
|time   V(typ)   V(min)   V(max)
0s        1.292uV    7.005uV    589.2nV
364ps     77.03uV    53.51uV    1.916mV
410ps     -440.8uV   74.49uV    94.81mV
473ps     6.476mV    -295.8uV   353.5mV
594ps     370.2mV    30.46mV    583mV
664ps     526.3mV    185.3mV    612.3mV
755ps     597.4mV    412.8mV    624.4mV
894ps     621.7mV    546.4mV    628.4mV
1.206ns   627.1mV    582.8mV    629.3mV
10ns      627.3mV    585.3mV    629.4mV
[Rising Waveform]
R_fixture= 50.000
V_fixture= 0.600
V_fixture_min= 0.583
V_fixture_max= 0.619
|time   V(typ)   V(min)   V(max)
0s        282.5mV    276.8mV    300.3mV
374ps     282.5mV    276.9mV    305.6mV
416ps     282.1mV    276.9mV    399.7mV
479ps     290.2mV    276.5mV    713.8mV
524ps     384.6mV    276.7mV    830.1mV
607ps     733mV      320.8mV    907.4mV
736ps     889mV      701.1mV    931.5mV
866ps     910.9mV    841.6mV    935.1mV
1.166ns   915.6mV    874.7mV    935.9mV
10ns      915.9mV    876.6mV    936mV
[Falling Waveform]
R_fixture= 50.000
V_fixture= 0.600
V_fixture_min= 0.583
V_fixture_max= 0.619
|time   V(typ)   V(min)   V(max)
0s        915.9mV    876.6mV    936mV
376ps     916.1mV    876.6mV    936mV
476ps     913.9mV    877.9mV    534.4mV
511ps     844.8mV    879.5mV    428.2mV
588ps     528.5mV    848.2mV    335.2mV
647ps     379.2mV    696.2mV    314.2mV
726ps     311.4mV    469.7mV    304.8mV
842ps     288.8mV    318.5mV    301.3mV
1.092ns   283mV      280.3mV    300.4mV
10ns      282.5mV    276.8mV    300.3mV
[Falling Waveform]
R_fixture= 50.000
V_fixture= 0.0
V_fixture_min= 0.0
V_fixture_max= 0.0
|time   V(typ)   V(min)   V(max)
0s        627.3mV    585.3mV    629.4mV
374ps     627.9mV    585.3mV    628.8mV
476ps     620.3mV    587.4mV    224.5mV
521ps     494.5mV    588.3mV    100.2mV
584ps     226.6mV    551.7mV    34.16mV
640ps     88.86mV    394.5mV    14.01mV
722ps     23.43mV    157.4mV    4.199mV
832ps     4.968mV    30.52mV    1.01mV
1.041ns   514.2uV    2.33mV     131.1uV
10ns      1.308uV    7.016uV    608nV
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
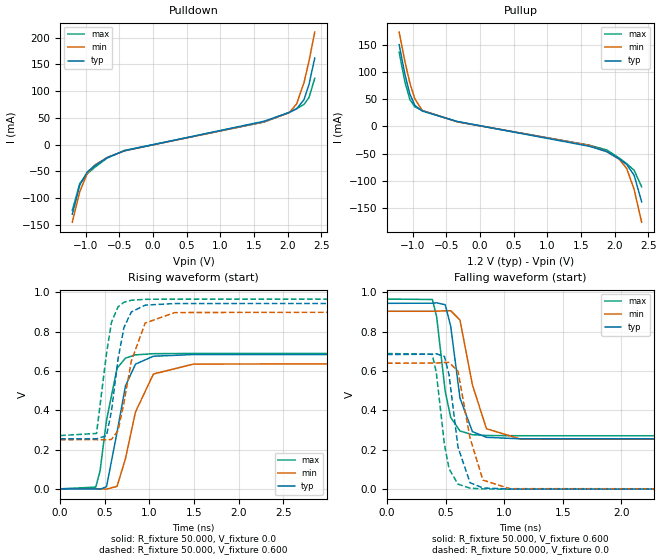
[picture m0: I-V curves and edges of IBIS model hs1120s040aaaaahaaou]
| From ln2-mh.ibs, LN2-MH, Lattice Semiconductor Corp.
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|   Model hs1120s040aaaaahaaou
[Model] hs1120s040aaaaahaaou
Model_type Output
Polarity   Non-Inverting
Enable   Active-High
Vmeas =  0.600V
Cref =  20.000pF
Rref =  50.000
Vref =  0.600V
C_comp   2.000pF   1.500pF   2.500pF
[Temperature Range]   25.000   0.125k   -40.000
[Voltage Range]   1.200V   1.160V   1.240V
[C Comp Corner]
C_comp   2.000pF   1.500pF   2.500pF
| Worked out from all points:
|   slope of the pulldown table from 0 to 0.18 V, typ, clamps not added: 36.9 ohm
|   slope of the pullup table from 0 to 0.18 V, typ, clamps not added: 37.3 ohm
|   rising waveform, R_fixture 50.000, V_fixture 0.0: 20-80 % time 158ps typ, 212ps min, 130ps max; typ from 0 V to 0.684 V
|   rising waveform, R_fixture 50.000, V_fixture 0.600: 20-80 % time 132ps typ, 177ps min, 109ps max; typ from 0.255 V to 0.943 V
|   falling waveform, R_fixture 50.000, V_fixture 0.600: 20-80 % time 98ps typ, 127ps min, 88ps max; typ from 0.943 V to 0.255 V
|   falling waveform, R_fixture 50.000, V_fixture 0.0: 20-80 % time 92.3ps typ, 115ps min, 85.9ps max; typ from 0.684 V to 0 V
[Pulldown]
|Voltage   I(typ)   I(min)   I(max)
-1.2V     -130.4mA   -145.2mA   -123.2mA
-1.089V   -76.06mA   -88.24mA   -72.96mA
-978mV    -51.12mA   -53.82mA   -54.4mA
-867mV    -39.66mA   -38.57mA   -42.73mA
-682mV    -24.46mA   -24.18mA   -25.24mA
-423mV    -11.56mA   -11.59mA   -10.92mA
1.649V    43.64mA    42.58mA    42.18mA
2.019V    59.89mA    59.32mA    60.3mA
2.13V     66.73mA    75.74mA    67.04mA
2.241V    84.04mA    116.1mA    75.18mA
2.315V    112.8mA    156.3mA    87.92mA
2.4V      161.6mA    210.3mA    123.8mA
[Pullup]
|Voltage   I(typ)   I(min)   I(max)
-1.2V     150mA      173.2mA    136.2mA
-1.115V   95.98mA    119.5mA    81.92mA
-1.041V   59.5mA     79.86mA    49.41mA
-967mV    38.64mA    50.65mA    35.94mA
-856mV    28.09mA    28.99mA    29.17mA
-338mV    9.116mA    8.575mA    8.54mA
1.623V    -36.48mA   -34.93mA   -34.51mA
1.882V    -46.27mA   -46.35mA   -43.16mA
2.067V    -59.74mA   -60.16mA   -58.07mA
2.178V    -69.72mA   -77.16mA   -68.48mA
2.289V    -89.63mA   -115.9mA   -80.62mA
2.4V      -138.5mA   -175.9mA   -110.9mA
[Ramp]
| variable   typ   min   max
dV/dt_r   0.410/0.159n   0.384/0.213n   0.413/0.130n
dV/dt_f   0.414/0.109n   0.397/0.147n   0.418/92.946p
R_load = 50.000
[Rising Waveform]
R_fixture= 50.000
V_fixture= 0.0
V_fixture_min= 0.0
V_fixture_max= 0.0
|time   V(typ)   V(min)   V(max)
0s        1.143uV    6.223uV    521.7nV
399ps     -290.3uV   67.49uV    8.882mV
447ps     -1.674mV   15.5uV     92.19mV
519ps     10.64mV    -1.203mV   348.9mV
637ps     287.8mV    12.42mV    613.1mV
731ps     522.9mV    153.4mV    665mV
843ps     634.1mV    390.5mV    681.3mV
1.044ns   674.4mV    584mV      687.4mV
1.493ns   683mV      634.6mV    688.6mV
10ns      683.6mV    639.6mV    688.7mV
[Rising Waveform]
R_fixture= 50.000
V_fixture= 0.600
V_fixture_min= 0.583
V_fixture_max= 0.619
|time   V(typ)   V(min)   V(max)
0s        254.7mV    249.8mV    271mV
407ps     254.3mV    249.9mV    281.7mV
519ps     270.5mV    249.3mV    688.2mV
575ps     396.4mV    251.2mV    848mV
649ps     662.8mV    297.2mV    926.4mV
715ps     821.2mV    439.9mV    949.3mV
797ps     899.9mV    650.2mV    959.1mV
952ps     934.3mV    843.3mV    963.8mV
1.283ns   942.5mV    896.6mV    965mV
10ns      943.4mV    903.1mV    965.2mV
[Falling Waveform]
R_fixture= 50.000
V_fixture= 0.600
V_fixture_min= 0.583
V_fixture_max= 0.619
|time   V(typ)   V(min)   V(max)
0s        943.4mV    903.1mV    965.1mV
388ps     944.3mV    903.2mV    962.8mV
424ps     946.1mV    903.5mV    874mV
497ps     936.2mV    905.6mV    496.4mV
544ps     826.2mV    905.9mV    364mV
623ps     462.2mV    858.7mV    295.4mV
729ps     292.3mV    530.3mV    276.5mV
849ps     263.3mV    306.8mV    272.5mV
1.139ns   255.6mV    254.7mV    271.2mV
10ns      254.7mV    249.8mV    271mV
[Falling Waveform]
R_fixture= 50.000
V_fixture= 0.0
V_fixture_min= 0.0
V_fixture_max= 0.0
|time   V(typ)   V(min)   V(max)
0s        683.6mV    639.6mV    688.7mV
386ps     685.2mV    639.8mV    684.7mV
421ps     687.2mV    640.4mV    592.1mV
490ps     673.9mV    643.2mV    227.8mV
530ps     579.8mV    643.2mV    103.1mV
606ps     213.4mV    598.8mV    25.61mV
709ps     32.79mV    259.6mV    5.015mV
819ps     6.261mV    46.09mV    1.209mV
1.049ns   624.4uV    2.5mV      154.3uV
10ns      1.158uV    6.231uV    540.3nV
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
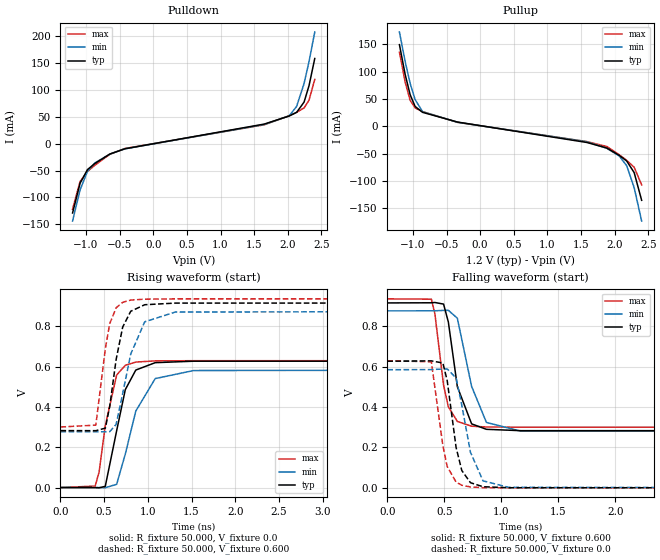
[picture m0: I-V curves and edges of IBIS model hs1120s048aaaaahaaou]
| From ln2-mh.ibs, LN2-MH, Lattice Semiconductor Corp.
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|   Model hs1120s048aaaaahaaou
[Model] hs1120s048aaaaahaaou
Model_type Output
Polarity   Non-Inverting
Enable   Active-High
Vmeas =  0.600V
Cref =  20.000pF
Rref =  50.000
Vref =  0.600V
C_comp   2.000pF   1.500pF   2.500pF
[Temperature Range]   25.000   0.125k   -40.000
[Voltage Range]   1.200V   1.160V   1.240V
[C Comp Corner]
C_comp   2.000pF   1.500pF   2.500pF
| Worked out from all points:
|   slope of the pulldown table from 0 to 0.18 V, typ, clamps not added: 44.5 ohm
|   slope of the pullup table from 0 to 0.18 V, typ, clamps not added: 44.9 ohm
|   rising waveform, R_fixture 50.000, V_fixture 0.0: 20-80 % time 169ps typ, 226ps min, 137ps max; typ from 0 V to 0.627 V
|   rising waveform, R_fixture 50.000, V_fixture 0.600: 20-80 % time 142ps typ, 190ps min, 115ps max; typ from 0.282 V to 0.916 V
|   falling waveform, R_fixture 50.000, V_fixture 0.600: 20-80 % time 105ps typ, 139ps min, 92.4ps max; typ from 0.916 V to 0.282 V
|   falling waveform, R_fixture 50.000, V_fixture 0.0: 20-80 % time 98.6ps typ, 124ps min, 90.5ps max; typ from 0.627 V to 0 V
[Pulldown]
|Voltage   I(typ)   I(min)   I(max)
-1.2V     -128.9mA   -143.8mA   -121.8mA
-1.089V   -73.85mA   -86.32mA   -70.61mA
-978mV    -48.21mA   -51.24mA   -51.6mA
-867mV    -36.76mA   -35.77mA   -40.02mA
-645mV    -19.29mA   -19.32mA   -19.79mA
-423mV    -9.615mA   -9.692mA   -9.044mA
1.649V    36.31mA    35.55mA    34.98mA
2.019V    51.34mA    51.54mA    51.84mA
2.13V     58.1mA     69.13mA    58.18mA
2.241V    77.15mA    111.6mA    66.35mA
2.315V    107.9mA    152.7mA    80.79mA
2.4V      158.2mA    207.4mA    119.5mA
[Pullup]
|Voltage   I(typ)   I(min)   I(max)
-1.2V     149.1mA    172.2mA    135.3mA
-1.115V   94.65mA    118.3mA    80.64mA
-1.041V   57.63mA    78.35mA    47.41mA
-967mV    36.14mA    48.7mA     33.41mA
-856mV    25.33mA    26.57mA    26.62mA
-338mV    7.596mA    7.177mA    7.095mA
1.586V    -29.78mA   -28.41mA   -28.15mA
1.882V    -39.92mA   -40.44mA   -37.1mA
2.067V    -53.43mA   -54.43mA   -52.11mA
2.178V    -63.6mA    -72.3mA    -62.57mA
2.289V    -84.85mA   -112.4mA   -75.03mA
2.4V      -135.5mA   -173.4mA   -107.4mA
[Ramp]
| variable   typ   min   max
dV/dt_r   0.376/0.169n   0.351/0.226n   0.378/0.138n
dV/dt_f   0.380/0.119n   0.365/0.164n   0.383/96.871p
R_load = 50.000
[Rising Waveform]
R_fixture= 50.000
V_fixture= 0.0
V_fixture_min= 0.0
V_fixture_max= 0.0
|time   V(typ)   V(min)   V(max)
0s        1.292uV    7.005uV    589.2nV
397ps     -239uV     71.17uV    7.302mV
442ps     -1.458mV   51.83uV    76.87mV
513ps     6.253mV    -1.073mV   307.5mV
643ps     282mV      16.23mV    558.2mV
742ps     485.9mV    166.3mV    606.6mV
862ps     582.9mV    379.4mV    622.5mV
1.084ns   619.5mV    540.5mV    628.3mV
1.524ns   626.8mV    580.5mV    629.3mV
10ns      627.3mV    585.3mV    629.4mV
[Rising Waveform]
R_fixture= 50.000
V_fixture= 0.600
V_fixture_min= 0.583
V_fixture_max= 0.619
|time   V(typ)   V(min)   V(max)
0s        282.5mV    276.8mV    300.3mV
405ps     282.1mV    276.9mV    309.7mV
514ps     294.8mV    276.3mV    690.4mV
564ps     403.5mV    277.5mV    813.4mV
637ps     635.1mV    313.3mV    891.5mV
712ps     796mV      466.6mV    919mV
804ps     874.5mV    662.3mV    930mV
964ps     906.9mV    822.2mV    934.6mV
1.314ns   915mV      870.6mV    935.9mV
10ns      915.9mV    876.6mV    936mV
[Falling Waveform]
R_fixture= 50.000
V_fixture= 0.600
V_fixture_min= 0.583
V_fixture_max= 0.619
|time   V(typ)   V(min)   V(max)
0s        915.9mV    876.6mV    936mV
386ps     916.6mV    876.7mV    934.6mV
417ps     918.1mV    876.9mV    862.7mV
493ps     910.1mV    878.9mV    508.9mV
535ps     821.4mV    879.4mV    401.6mV
614ps     500.9mV    840.1mV    328.9mV
739ps     316.9mV    502.5mV    305.3mV
869ps     289.9mV    324mV      301.4mV
1.168ns   283.2mV    281.1mV    300.4mV
10ns      282.5mV    276.8mV    300.3mV
[Falling Waveform]
R_fixture= 50.000
V_fixture= 0.0
V_fixture_min= 0.0
V_fixture_max= 0.0
|time   V(typ)   V(min)   V(max)
0s        627.3mV    585.3mV    629.4mV
386ps     628.9mV    585.5mV    624.5mV
487ps     618.4mV    588.7mV    208.5mV
525ps     531.3mV    589mV      105.4mV
603ps     199.9mV    543.9mV    28.35mV
653ps     85.88mV    409.3mV    13.05mV
729ps     25.47mV    176.1mV    4.406mV
839ps     5.581mV    34.81mV    1.117mV
1.063ns   599.6uV    2.461mV    139.9uV
10ns      1.309uV    7.016uV    608.3nV
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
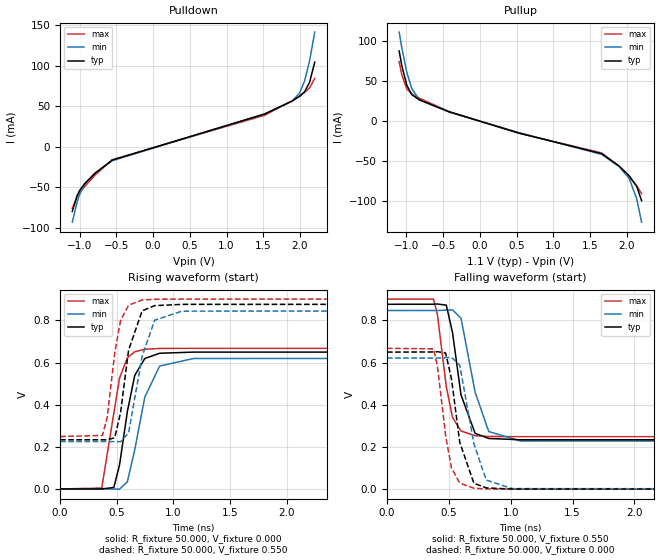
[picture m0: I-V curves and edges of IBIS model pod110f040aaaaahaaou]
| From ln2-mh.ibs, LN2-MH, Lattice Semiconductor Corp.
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|   Model pod110f040aaaaahaaou
[Model] pod110f040aaaaahaaou
Model_type Output
Polarity   Non-Inverting
Enable   Active-High
Vmeas =  0.550V
Cref =  20.000pF
Rref =  50.000
Vref =  0.600V
C_comp   2.000pF   1.500pF   2.500pF
[Temperature Range]   25.000   0.125k   -40.000
[Voltage Range]   1.100V   1.070V   1.130V
[C Comp Corner]
C_comp   2.000pF   1.500pF   2.500pF
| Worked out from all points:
|   slope of the pulldown table from 0 to 0.165 V, typ, clamps not added: 36.9 ohm
|   slope of the pullup table from 0 to 0.165 V, typ, clamps not added: 34.3 ohm
|   rising waveform, R_fixture 50.000, V_fixture 0.000: 20-80 % time 119ps typ, 144ps min, 107ps max; typ from 0 V to 0.65 V
|   rising waveform, R_fixture 50.000, V_fixture 0.550: 20-80 % time 102ps typ, 122ps min, 95.3ps max; typ from 0.233 V to 0.876 V
|   falling waveform, R_fixture 50.000, V_fixture 0.550: 20-80 % time 99.4ps typ, 123ps min, 90.8ps max; typ from 0.876 V to 0.233 V
|   falling waveform, R_fixture 50.000, V_fixture 0.000: 20-80 % time 96.2ps typ, 116ps min, 89.1ps max; typ from 0.65 V to 0 V
[Pulldown]
|Voltage   I(typ)   I(min)   I(max)
-1.1V     -80.13mA   -93.34mA   -76.18mA
-1.032V   -59.99mA   -67.81mA   -61.23mA
-998mV    -53.9mA    -58.64mA   -56.69mA
-930mV    -45.61mA   -46.27mA   -49.16mA
-794mV    -33.29mA   -32.75mA   -35.47mA
-556mV    -16.64mA   -17.34mA   -16.19mA
1.518V    40.3mA     40.42mA    38.8mA
1.892V    56.34mA    56.06mA    56.7mA
1.994V    62.1mA     66.32mA    62.84mA
2.062V    67.75mA    81.17mA    67.18mA
2.13V     79.49mA    106.1mA    72.58mA
2.2V      104.4mA    141.5mA    84.35mA
[Pullup]
|Voltage   I(typ)   I(min)   I(max)
-1.1V     87.18mA    110.7mA    73.85mA
-1.064V   69.01mA    91.21mA    57.57mA
-996mV    44.44mA    60.61mA    39.84mA
-928mV    32.85mA    40.3mA     33.52mA
-826mV    26.27mA    26.39mA    28.39mA
-418mV    11.37mA    10.99mA    11.45mA
534mV     -15.31mA   -14.68mA   -15.34mA
1.656V    -40.76mA   -41.63mA   -39.88mA
1.894V    -56.26mA   -56.96mA   -56.48mA
2.03V     -68.28mA   -71.52mA   -69.91mA
2.132V    -81.32mA   -96.73mA   -80.93mA
2.2V      -99.48mA   -126.2mA   -90.7mA
[Ramp]
| variable   typ   min   max
dV/dt_r   0.376/0.119n   0.359/0.144n   0.386/0.107n
dV/dt_f   0.379/0.106n   0.371/0.137n   0.381/93.306p
R_load = 50.000
[Rising Waveform]
R_fixture = 50.000
V_fixture = 0.000
V_fixture_min = 0.000
V_fixture_max = 0.000
|  time   V(typ)   V(min)   V(max)
0s        1.497uV    7.052uV    0V
367ps     67.98uV    48.12uV    4.108mV
474ps     7.039mV    -342.6uV   360.3mV
524ps     114mV      -959.7uV   525.7mV
593ps     366.7mV    34.07mV    622.3mV
658ps     538.4mV    184.8mV    651.1mV
747ps     619mV      435.8mV    662.9mV
878ps     644mV      583.1mV    666.6mV
1.177ns   649.4mV    619mV      667.4mV
10ns      649.7mV    621.3mV    667.5mV
[Rising Waveform]
R_fixture = 50.000
V_fixture = 0.550
V_fixture_min = 0.534
V_fixture_max = 0.568
|  time   V(typ)   V(min)   V(max)
0s        233.5mV    224.9mV    248.7mV
374ps     233.5mV    225mV      254.3mV
416ps     233.1mV    225mV      342.8mV
482ps     243.3mV    224.5mV    647.1mV
533ps     361.8mV    224.6mV    799.2mV
604ps     659.1mV    265.5mV    871.9mV
724ps     845.4mV    630mV      896.7mV
834ps     869.9mV    800.7mV    900.1mV
1.074ns   875.9mV    843.8mV    901mV
10ns      876.3mV    846.9mV    901.1mV
[Falling Waveform]
R_fixture = 50.000
V_fixture = 0.550
V_fixture_min = 0.534
V_fixture_max = 0.568
|  time   V(typ)   V(min)   V(max)
0s        876.3mV    846.9mV    901.1mV
376ps     876.6mV    846.9mV    900.9mV
407ps     877.8mV    847mV      828.7mV
479ps     872.3mV    848.4mV    486.6mV
529ps     743.5mV    850.1mV    340.6mV
598ps     447mV      810.7mV    275.7mV
712ps     264.6mV    459.9mV    253.4mV
822ps     240.3mV    273.2mV    249.9mV
1.078ns   234.1mV    228.5mV    248.8mV
10ns      233.5mV    224.9mV    248.7mV
[Falling Waveform]
R_fixture = 50.000
V_fixture = 0.000
V_fixture_min = 0.000
V_fixture_max = 0.000
|  time   V(typ)   V(min)   V(max)
0s        649.7mV    621.3mV    667.5mV
376ps     650.3mV    621.3mV    665.2mV
407ps     651.8mV    621.6mV    584.7mV
474ps     645.2mV    623.3mV    252.9mV
521ps     522.7mV    624.5mV    100.7mV
588ps     221.6mV    587.3mV    28.92mV
702ps     28.18mV    216.1mV    4.489mV
802ps     6.018mV    43.27mV    1.146mV
1.012ns   560.7uV    2.661mV    154.2uV
10ns      1.497uV    7.052uV    0V
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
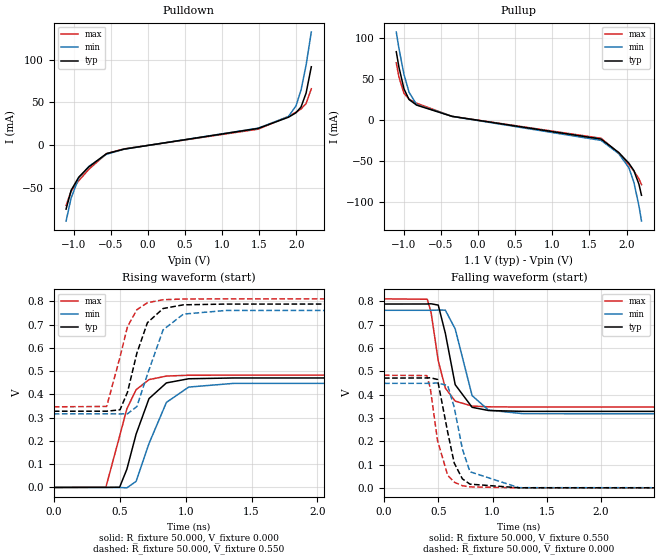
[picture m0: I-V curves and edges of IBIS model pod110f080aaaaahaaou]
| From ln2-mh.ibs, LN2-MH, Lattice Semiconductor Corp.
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|   Model pod110f080aaaaahaaou
[Model] pod110f080aaaaahaaou
Model_type Output
Polarity   Non-Inverting
Enable   Active-High
Vmeas =  0.550V
Cref =  20.000pF
Rref =  50.000
Vref =  0.600V
C_comp   2.000pF   1.500pF   2.500pF
[Temperature Range]   25.000   0.125k   -40.000
[Voltage Range]   1.100V   1.070V   1.130V
[C Comp Corner]
C_comp   2.000pF   1.500pF   2.500pF
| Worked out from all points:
|   slope of the pulldown table from 0 to 0.165 V, typ, clamps not added: 73.8 ohm
|   slope of the pullup table from 0 to 0.165 V, typ, clamps not added: 65.1 ohm
|   rising waveform, R_fixture 50.000, V_fixture 0.000: 20-80 % time 155ps typ, 179ps min, 139ps max; typ from 0 V to 0.471 V
|   rising waveform, R_fixture 50.000, V_fixture 0.550: 20-80 % time 135ps typ, 155ps min, 121ps max; typ from 0.328 V to 0.789 V
|   falling waveform, R_fixture 50.000, V_fixture 0.550: 20-80 % time 120ps typ, 141ps min, 110ps max; typ from 0.789 V to 0.328 V
|   falling waveform, R_fixture 50.000, V_fixture 0.000: 20-80 % time 115ps typ, 130ps min, 105ps max; typ from 0.471 V to 0 V
[Pulldown]
|Voltage   I(typ)   I(min)   I(max)
-1.1V     -74.32mA   -88.15mA   -70.01mA
-1.032V   -52.39mA   -61.23mA   -53.47mA
-930mV    -37.09mA   -38.15mA   -41.2mA
-794mV    -25.11mA   -24.54mA   -27.91mA
-556mV    -9.618mA   -10.36mA   -9.575mA
-318mV    -4.323mA   -4.427mA   -4.063mA
1.484V    19.76mA    20.03mA    18.88mA
1.892V    32.77mA    33.6mA     33.64mA
1.994V    37.99mA    46.04mA    38.71mA
2.062V    44.81mA    64.59mA    42.51mA
2.13V     60.93mA    93.6mA     48.72mA
2.2V      91.63mA    132.1mA    65.98mA
[Pullup]
|Voltage   I(typ)   I(min)   I(max)
-1.1V     83.6mA     107.6mA    70.02mA
-1.064V   64.64mA    87.55mA    52.63mA
-996mV    38.2mA     55.74mA    32.73mA
-928mV    25.26mA    34.1mA     25.72mA
-826mV    18.43mA    19.13mA    20.77mA
-350mV    4.781mA    4.719mA    4.756mA
1.656V    -22.96mA   -24.57mA   -21.98mA
1.894V    -39.37mA   -40.74mA   -39.91mA
2.03V     -52.37mA   -57.85mA   -54.25mA
2.098V    -61.45mA   -75.77mA   -62.01mA
2.166V    -78.13mA   -104.6mA   -71.44mA
2.2V      -91.52mA   -122.9mA   -78.53mA
[Ramp]
| variable   typ   min   max
dV/dt_r   0.283/0.155n   0.269/0.179n   0.290/0.139n
dV/dt_f   0.266/0.133n   0.261/0.162n   0.264/0.119n
R_load = 50.000
[Rising Waveform]
R_fixture = 50.000
V_fixture = 0.000
V_fixture_min = 0.000
V_fixture_max = 0.000
|  time   V(typ)   V(min)   V(max)
0s        1.577uV    10.97uV    1.615uV
395ps     184.2uV    131.5uV    1.164mV
499ps     902.7uV    -259.6uV   220.4mV
554ps     78.37mV    -1.745mV   338.5mV
624ps     229.2mV    26.08mV    420.3mV
722ps     382.2mV    189.1mV    463.9mV
854ps     449.8mV    365.9mV    479.2mV
1.023ns   467.6mV    431.8mV    482.7mV
1.363ns   471mV      447.7mV    483.3mV
10ns      471.2mV    448.6mV    483.4mV
[Rising Waveform]
R_fixture = 50.000
V_fixture = 0.550
V_fixture_min = 0.534
V_fixture_max = 0.568
|  time   V(typ)   V(min)   V(max)
0s        327.9mV    316.5mV    346.8mV
401ps     328mV      316.6mV    348.5mV
502ps     334mV      316.4mV    560.8mV
559ps     410mV      316.8mV    692.1mV
630ps     577.8mV    348.3mV    764.7mV
710ps     708.9mV    486.4mV    794.8mV
829ps     769.8mV    678.1mV    807.6mV
983ps     785.7mV    745.7mV    810.7mV
1.303ns   788.9mV    761.3mV    811.3mV
10ns      789.1mV    762.2mV    811.3mV
[Falling Waveform]
R_fixture = 50.000
V_fixture = 0.550
V_fixture_min = 0.534
V_fixture_max = 0.568
|  time   V(typ)   V(min)   V(max)
0s        789.1mV    762.2mV    811.3mV
399ps     789.3mV    762.2mV    809.7mV
434ps     790.2mV    762.2mV    752.4mV
500ps     784.5mV    763.2mV    544.9mV
565ps     664.1mV    762.9mV    428.6mV
656ps     442.9mV    682.4mV    372.4mV
812ps     345.8mV    395.9mV    351.1mV
963ps     332mV      333.6mV    347.9mV
1.282ns   328.4mV    318.4mV    346.9mV
10ns      327.9mV    316.5mV    346.8mV
[Falling Waveform]
R_fixture = 50.000
V_fixture = 0.000
V_fixture_min = 0.000
V_fixture_max = 0.000
|  time   V(typ)   V(min)   V(max)
0s        471.2mV    448.6mV    483.4mV
394ps     471.8mV    448.7mV    481.9mV
426ps     472.6mV    448.9mV    429.5mV
493ps     465.4mV    450.2mV    203.6mV
587ps     238.7mV    439.3mV    53.92mV
647ps     106.7mV    346.1mV    24.19mV
722ps     38.75mV    167.3mV    9.314mV
792ps     15.91mV    69.1mV     4.044mV
1.243ns   278.4uV    801.6uV    112.5uV
10ns      1.577uV    10.97uV    1.615uV
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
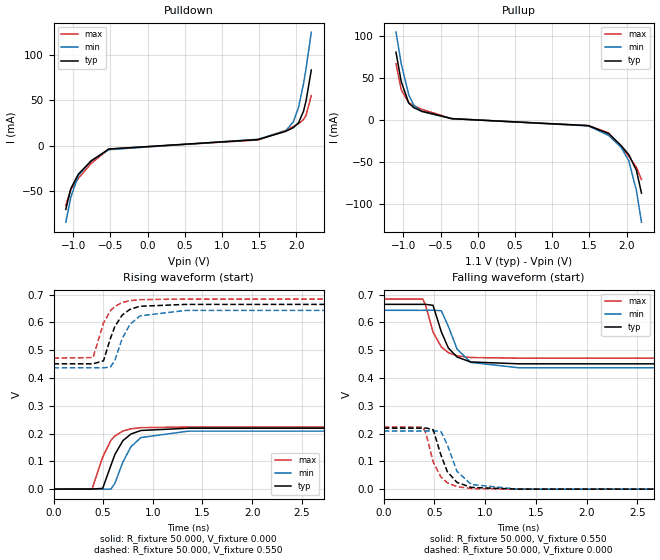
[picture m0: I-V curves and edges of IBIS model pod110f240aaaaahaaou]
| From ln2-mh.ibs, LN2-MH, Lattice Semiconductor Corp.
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|   Model pod110f240aaaaahaaou
[Model] pod110f240aaaaahaaou
Model_type Output
Polarity   Non-Inverting
Enable   Active-High
Vmeas =  0.550V
Cref =  20.000pF
Rref =  50.000
Vref =  0.600V
C_comp   2.000pF   1.500pF   2.500pF
[Temperature Range]   25.000   0.125k   -40.000
[Voltage Range]   1.100V   1.070V   1.130V
[C Comp Corner]
C_comp   2.000pF   1.500pF   2.500pF
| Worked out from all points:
|   slope of the pulldown table from 0 to 0.165 V, typ, clamps not added: 226 ohm
|   slope of the pullup table from 0 to 0.165 V, typ, clamps not added: 189 ohm
|   rising waveform, R_fixture 50.000, V_fixture 0.000: 20-80 % time 160ps typ, 174ps min, 149ps max; typ from 0 V to 0.219 V
|   rising waveform, R_fixture 50.000, V_fixture 0.550: 20-80 % time 145ps typ, 159ps min, 135ps max; typ from 0.451 V to 0.665 V
|   falling waveform, R_fixture 50.000, V_fixture 0.550: 20-80 % time 141ps typ, 153ps min, 134ps max; typ from 0.665 V to 0.451 V
|   falling waveform, R_fixture 50.000, V_fixture 0.000: 20-80 % time 136ps typ, 146ps min, 130ps max; typ from 0.219 V to 0 V
[Pulldown]
|Voltage   I(typ)   I(min)   I(max)
-1.1V     -70.48mA   -84.6mA    -66.03mA
-1.032V   -47.41mA   -56.86mA   -48.41mA
-930mV    -31.43mA   -32.77mA   -35.94mA
-760mV    -17.07mA   -16.65mA   -19.85mA
-522mV    -3.767mA   -4.526mA   -3.778mA
1.484V    6.645mA    7.035mA    6.22mA
1.858V    15.77mA    16.54mA    16.82mA
1.96V     19.93mA    26.39mA    21.06mA
2.028V    25.15mA    42.13mA    24.19mA
2.096V    38.09mA    68.49mA    28.9mA
2.13V     49.57mA    85.28mA    33.6mA
2.2V      83.5mA     125.4mA    55.21mA
[Pullup]
|Voltage   I(typ)   I(min)   I(max)
-1.1V     81.07mA    105.2mA    67.43mA
-1.03V    46.16mA    67.55mA    36.49mA
-928mV    20.26mA    29.94mA    20.57mA
-860mV    14.8mA     17.69mA    17.15mA
-758mV    10.74mA    10.27mA    13.03mA
-350mV    1.669mA    1.76mA     1.665mA
1.486V    -6.674mA   -6.996mA   -6.556mA
1.758V    -16.1mA    -18.33mA   -15.41mA
1.928V    -30.66mA   -32.78mA   -31.94mA
2.03V     -41.41mA   -48.75mA   -43.49mA
2.132V    -60.12mA   -84.3mA    -56.57mA
2.2V      -87.31mA   -122.1mA   -71.2mA
[Ramp]
| variable   typ   min   max
dV/dt_r   0.132/0.160n   0.125/0.174n   0.134/0.149n
dV/dt_f   0.119/0.150n   0.117/0.169n   0.115/0.140n
R_load = 50.000
[Rising Waveform]
R_fixture = 50.000
V_fixture = 0.000
V_fixture_min = 0.000
V_fixture_max = 0.000
|  time   V(typ)   V(min)   V(max)
0s        2.527uV    12.65uV    1.11uV
389ps     346.7uV    169.2uV    728.8uV
495ps     2.515mV    -39.9uV    115.4mV
578ps     85.34mV    -195.5uV   175.5mV
618ps     124.6mV    20.99mV    191.2mV
698ps     174mV      96.7mV     208.8mV
779ps     198mV      152mV      216.8mV
880ps     210.9mV    185.5mV    221mV
1.36ns    219.1mV    208.6mV    223.5mV
10ns      219.3mV    209.1mV    223.6mV
[Rising Waveform]
R_fixture = 50.000
V_fixture = 0.550
V_fixture_min = 0.534
V_fixture_max = 0.568
|  time   V(typ)   V(min)   V(max)
0s        450.6mV    436.2mV    471.2mV
398ps     450.8mV    436.4mV    473.3mV
503ps     461.4mV    436.2mV    597.2mV
574ps     543.1mV    439.7mV    642.3mV
617ps     584.4mV    462.6mV    657.1mV
691ps     625.9mV    540.7mV    671.2mV
769ps     646.5mV    592.6mV    678mV
871ps     657.8mV    623.3mV    681.6mV
1.331ns   664.5mV    642.8mV    683.7mV
10ns      664.7mV    643.2mV    683.7mV
[Falling Waveform]
R_fixture = 50.000
V_fixture = 0.550
V_fixture_min = 0.534
V_fixture_max = 0.568
|  time   V(typ)   V(min)   V(max)
0s        664.7mV    643.2mV    683.7mV
385ps     664.6mV    643.1mV    683.6mV
411ps     664.8mV    643.2mV    663.6mV
486ps     661.2mV    643.6mV    565.5mV
568ps     565.8mV    641.6mV    511.3mV
637ps     507.8mV    585.4mV    491.1mV
723ps     475.2mV    504.1mV    479.6mV
857ps     457.5mV    456mV      473.5mV
1.331ns   450.8mV    436.6mV    471.2mV
10ns      450.6mV    436.2mV    471.2mV
[Falling Waveform]
R_fixture = 50.000
V_fixture = 0.000
V_fixture_min = 0.000
V_fixture_max = 0.000
|  time   V(typ)   V(min)   V(max)
0s        219.3mV    209.1mV    223.6mV
386ps     219.4mV    209.1mV    223mV
417ps     219.9mV    209.1mV    199.5mV
488ps     213.8mV    210mV      97.41mV
564ps     122.8mV    207.5mV    43.7mV
627ps     63.04mV    159.7mV    22.96mV
722ps     24.34mV    64.36mV    8.925mV
863ps     6.321mV    16.69mV    2.313mV
1.313ns   169.4uV    422.4uV    71.99uV
10ns      2.527uV    12.65uV    1.11uV
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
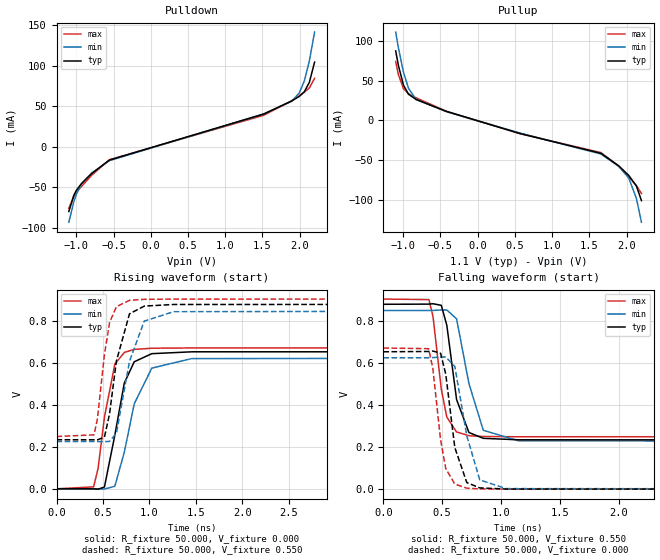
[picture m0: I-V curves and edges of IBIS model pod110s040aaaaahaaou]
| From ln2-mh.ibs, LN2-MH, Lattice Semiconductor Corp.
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|   Model pod110s040aaaaahaaou
[Model] pod110s040aaaaahaaou
Model_type Output
Polarity   Non-Inverting
Enable   Active-High
Vmeas =  0.550V
Cref =  20.000pF
Rref =  50.000
Vref =  0.600V
C_comp   2.000pF   1.500pF   2.500pF
[Temperature Range]   25.000   0.125k   -40.000
[Voltage Range]   1.100V   1.070V   1.130V
[C Comp Corner]
C_comp   2.000pF   1.500pF   2.500pF
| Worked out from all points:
|   slope of the pulldown table from 0 to 0.165 V, typ, clamps not added: 36.9 ohm
|   slope of the pullup table from 0 to 0.165 V, typ, clamps not added: 34 ohm
|   rising waveform, R_fixture 50.000, V_fixture 0.000: 20-80 % time 156ps typ, 200ps min, 128ps max; typ from 0 V to 0.652 V
|   rising waveform, R_fixture 50.000, V_fixture 0.550: 20-80 % time 131ps typ, 164ps min, 108ps max; typ from 0.233 V to 0.878 V
|   falling waveform, R_fixture 50.000, V_fixture 0.550: 20-80 % time 98.6ps typ, 125ps min, 88.3ps max; typ from 0.878 V to 0.233 V
|   falling waveform, R_fixture 50.000, V_fixture 0.000: 20-80 % time 93.6ps typ, 114ps min, 86.2ps max; typ from 0.652 V to 0 V
[Pulldown]
|Voltage   I(typ)   I(min)   I(max)
-1.1V     -80.13mA   -93.34mA   -76.18mA
-1.032V   -59.99mA   -67.81mA   -61.23mA
-998mV    -53.9mA    -58.64mA   -56.69mA
-930mV    -45.61mA   -46.27mA   -49.16mA
-794mV    -33.29mA   -32.75mA   -35.47mA
-556mV    -16.64mA   -17.34mA   -16.19mA
1.518V    40.3mA     40.42mA    38.8mA
1.892V    56.34mA    56.06mA    56.7mA
1.994V    62.1mA     66.32mA    62.84mA
2.062V    67.75mA    81.17mA    67.18mA
2.13V     79.49mA    106.1mA    72.58mA
2.2V      104.4mA    141.5mA    84.35mA
[Pullup]
|Voltage   I(typ)   I(min)   I(max)
-1.1V     87.18mA    110.7mA    73.85mA
-1.064V   69.01mA    91.21mA    57.57mA
-996mV    44.44mA    60.61mA    39.84mA
-928mV    32.85mA    40.3mA     33.52mA
-826mV    26.27mA    26.39mA    28.39mA
-418mV    11.37mA    10.99mA    11.45mA
568mV     -16.38mA   -15.71mA   -16.43mA
1.656V    -41.13mA   -42.01mA   -40.25mA
1.894V    -56.77mA   -57.49mA   -56.99mA
2.03V     -68.91mA   -72.18mA   -70.55mA
2.132V    -82.06mA   -97.62mA   -81.67mA
2.2V      -100.4mA   -127.4mA   -91.53mA
[Ramp]
| variable   typ   min   max
dV/dt_r   0.376/0.157n   0.359/0.200n   0.386/0.128n
dV/dt_f   0.379/0.108n   0.371/0.145n   0.381/92.566p
R_load = 50.000
[Rising Waveform]
R_fixture = 50.000
V_fixture = 0.000
V_fixture_min = 0.000
V_fixture_max = 0.000
|  time   V(typ)   V(min)   V(max)
0s        1.497uV    7.052uV    0V
399ps     -300.7uV   71.63uV    9.145mV
447ps     -1.731mV   15.87uV    95.35mV
516ps     8.418mV    -1.179mV   340mV
628ps     254.9mV    12.17mV    592.9mV
730ps     502.9mV    174mV      648.5mV
837ps     604.1mV    404.1mV    663mV
1.026ns   642.7mV    574mV      668.6mV
1.456ns   651.5mV    619.2mV    669.9mV
10ns      652.2mV    623.7mV    670mV
[Rising Waveform]
R_fixture = 50.000
V_fixture = 0.550
V_fixture_min = 0.534
V_fixture_max = 0.568
|  time   V(typ)   V(min)   V(max)
0s        233.5mV    224.9mV    248.7mV
404ps     233.1mV    225mV      256.6mV
440ps     232.8mV    224.9mV    331.7mV
516ps     245.8mV    224.3mV    638.1mV
571ps     356.1mV    225.5mV    790.6mV
645ps     607.8mV    263.9mV    866.2mV
786ps     832.3mV    606.6mV    896.4mV
945ps     868.9mV    797.4mV    901.1mV
1.261ns   876.6mV    842.4mV    902.2mV
10ns      877.6mV    848.1mV    902.4mV
[Falling Waveform]
R_fixture = 50.000
V_fixture = 0.550
V_fixture_min = 0.534
V_fixture_max = 0.568
|  time   V(typ)   V(min)   V(max)
0s        877.6mV    848.1mV    902.4mV
387ps     878.4mV    848.2mV    899.9mV
422ps     880.2mV    848.5mV    818.3mV
492ps     872.7mV    850.5mV    474.9mV
539ps     778.2mV    850.8mV    342.2mV
622ps     425.4mV    808.5mV    271.6mV
727ps     268.9mV    501.2mV    253.8mV
849ps     241.3mV    279.5mV    250mV
1.149ns   234.3mV    229.5mV    248.8mV
10ns      233.5mV    224.9mV    248.7mV
[Falling Waveform]
R_fixture = 50.000
V_fixture = 0.000
V_fixture_min = 0.000
V_fixture_max = 0.000
|  time   V(typ)   V(min)   V(max)
0s        652.2mV    623.7mV    670mV
384ps     653.6mV    623.9mV    667mV
420ps     655.8mV    624.5mV    574.7mV
486ps     645mV      627.3mV    233.8mV
530ps     546.2mV    627.2mV    98.01mV
607ps     197.3mV    582.5mV    24.05mV
709ps     31.21mV    253mV      4.753mV
819ps     5.965mV    44.01mV    1.145mV
1.043ns   626.9uV    2.639mV    163.2uV
10ns      1.497uV    7.052uV    0V
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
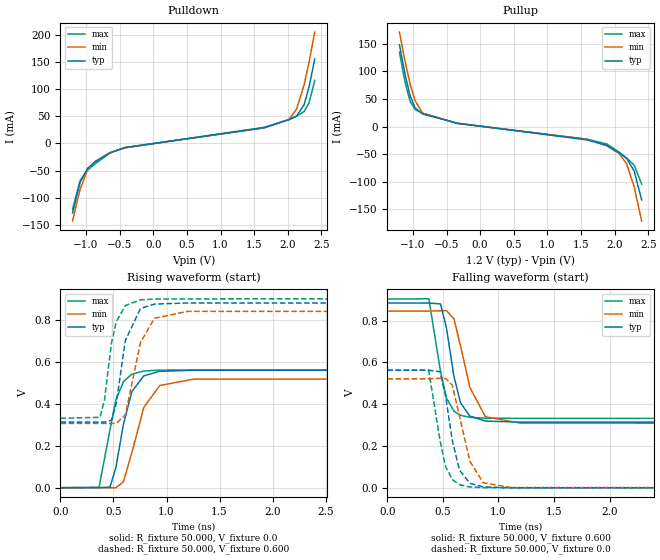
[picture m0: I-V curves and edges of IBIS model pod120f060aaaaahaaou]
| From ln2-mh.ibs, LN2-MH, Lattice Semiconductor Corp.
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|   Model pod120f060aaaaahaaou
[Model] pod120f060aaaaahaaou
Model_type Output
Polarity   Non-Inverting
Enable   Active-High
Vmeas =  0.600V
Cref =  20.000pF
Rref =  50.000
Vref =  0.600V
C_comp   2.000pF   1.500pF   2.500pF
[Temperature Range]   25.000   0.125k   -40.000
[Voltage Range]   1.200V   1.160V   1.240V
[C Comp Corner]
C_comp   2.000pF   1.500pF   2.500pF
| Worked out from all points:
|   slope of the pulldown table from 0 to 0.18 V, typ, clamps not added: 54.8 ohm
|   slope of the pullup table from 0 to 0.18 V, typ, clamps not added: 55.5 ohm
|   rising waveform, R_fixture 50.000, V_fixture 0.0: 20-80 % time 137ps typ, 172ps min, 122ps max; typ from 0 V to 0.562 V
|   rising waveform, R_fixture 50.000, V_fixture 0.600: 20-80 % time 111ps typ, 140ps min, 101ps max; typ from 0.314 V to 0.884 V
|   falling waveform, R_fixture 50.000, V_fixture 0.600: 20-80 % time 114ps typ, 147ps min, 103ps max; typ from 0.884 V to 0.314 V
|   falling waveform, R_fixture 50.000, V_fixture 0.0: 20-80 % time 110ps typ, 137ps min, 103ps max; typ from 0.562 V to 0 V
[Pulldown]
|Voltage   I(typ)   I(min)   I(max)
-1.2V     -127.6mA   -142.5mA   -120.7mA
-1.089V   -71.86mA   -84.58mA   -68.57mA
-978mV    -45.57mA   -48.89mA   -49.13mA
-867mV    -34.1mA    -33.22mA   -37.62mA
-645mV    -16.91mA   -17.02mA   -17.62mA
-423mV    -7.819mA   -7.942mA   -7.369mA
1.649V    29.6mA     29.08mA    28.54mA
2.019V    43.56mA    44.45mA    44.25mA
2.13V     50.29mA    63.23mA    50.23mA
2.241V    71.16mA    107.5mA    58.54mA
2.315V    103.7mA    149.5mA    74.75mA
2.4V      155.2mA    204.8mA    116mA
[Pullup]
|Voltage   I(typ)   I(min)   I(max)
-1.2V     148.2mA    171.3mA    134.6mA
-1.115V   93.42mA    117.2mA    79.51mA
-1.041V   55.91mA    76.92mA    45.64mA
-967mV    33.83mA    46.87mA    31.12mA
-856mV    22.76mA    24.27mA    24.31mA
-338mV    6.161mA    5.836mA    5.775mA
1.586V    -24.03mA   -22.97mA   -22.74mA
1.882V    -33.88mA   -34.76mA   -31.47mA
2.067V    -47.43mA   -48.94mA   -46.55mA
2.178V    -57.8mA    -67.71mA   -57.04mA
2.289V    -80.43mA   -109.2mA   -69.86mA
2.4V      -132.7mA   -171mA     -104.2mA
[Ramp]
| variable   typ   min   max
dV/dt_r   0.337/0.137n   0.313/0.172n   0.338/0.122n
dV/dt_f   0.343/0.125n   0.328/0.169n   0.344/0.105n
R_load = 50.000
[Rising Waveform]
R_fixture= 50.000
V_fixture= 0.0
V_fixture_min= 0.0
V_fixture_max= 0.0
|time   V(typ)   V(min)   V(max)
0s        1.465uV    7.91uV     665.2nV
364ps     77.11uV    62.65uV    2.06mV
467ps     3.06mV     -191.2uV   277.1mV
522ps     94.84mV    -682uV     419.2mV
594ps     304.3mV    28.67mV    507.7mV
674ps     460.3mV    169.4mV    543.6mV
786ps     535.3mV    384.4mV    558.4mV
936ps     556.9mV    489mV      562.4mV
1.256ns   561.8mV    519.4mV    563.2mV
10ns      562.1mV    521.7mV    563.3mV
[Rising Waveform]
R_fixture= 50.000
V_fixture= 0.600
V_fixture_min= 0.583
V_fixture_max= 0.619
|time   V(typ)   V(min)   V(max)
0s        314mV      307.6mV    332.3mV
373ps     314mV      307.6mV    336.7mV
415ps     313.7mV    307.6mV    418.8mV
481ps     322.9mV    307.3mV    692.1mV
526ps     402.7mV    307.6mV    794.2mV
612ps     705.1mV    348.8mV    871.8mV
755ps     857.6mV    695mV      898.8mV
886ps     878.6mV    810.7mV    902.5mV
1.195ns   883.7mV    843.5mV    903.4mV
10ns      883.9mV    845.6mV    903.5mV
[Falling Waveform]
R_fixture= 50.000
V_fixture= 0.600
V_fixture_min= 0.583
V_fixture_max= 0.619
|time   V(typ)   V(min)   V(max)
0s        883.9mV    845.6mV    903.5mV
374ps     884.1mV    845.6mV    903.9mV
479ps     879.5mV    846.9mV    555.5mV
532ps     765mV      847.9mV    428.9mV
599ps     534.4mV    809.1mV    367.3mV
659ps     406.6mV    679.1mV    347.1mV
743ps     343.1mV    480.3mV    337.1mV
883ps     319.3mV    340.1mV    333.2mV
1.199ns   314.3mV    309.6mV    332.3mV
10ns      314mV      307.6mV    332.3mV
[Falling Waveform]
R_fixture= 50.000
V_fixture= 0.0
V_fixture_min= 0.0
V_fixture_max= 0.0
|time   V(typ)   V(min)   V(max)
0s        562mV      521.7mV    563.2mV
372ps     562.6mV    521.7mV    562.7mV
474ps     555.7mV    523.6mV    227.7mV
523ps     443.6mV    524mV      103.3mV
584ps     228.6mV    492.2mV    39.82mV
649ps     85.44mV    344.7mV    15.32mV
742ps     21.83mV    128.8mV    4.262mV
862ps     4.572mV    24.75mV    970.8uV
1.113ns   360.4uV    1.562mV    94.16uV
10ns      1.483uV    7.926uV    686.8nV
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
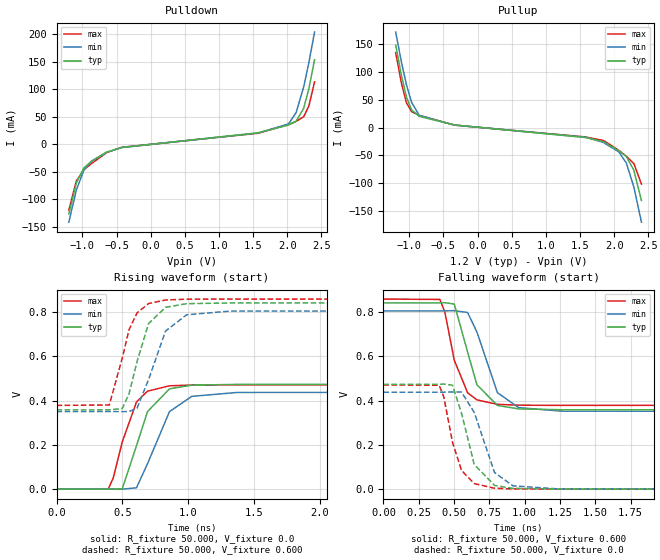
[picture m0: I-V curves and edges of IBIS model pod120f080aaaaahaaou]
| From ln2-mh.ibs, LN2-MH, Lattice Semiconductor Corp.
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|   Model pod120f080aaaaahaaou
[Model] pod120f080aaaaahaaou
Model_type Output
Polarity   Non-Inverting
Enable   Active-High
Vmeas =  0.600V
Cref =  20.000pF
Rref =  50.000
Vref =  0.600V
C_comp   2.000pF   1.500pF   2.500pF
[Temperature Range]   25.000   0.125k   -40.000
[Voltage Range]   1.200V   1.160V   1.240V
[C Comp Corner]
C_comp   2.000pF   1.500pF   2.500pF
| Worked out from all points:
|   slope of the pulldown table from 0 to 0.18 V, typ, clamps not added: 73.8 ohm
|   slope of the pullup table from 0 to 0.18 V, typ, clamps not added: 74.4 ohm
|   rising waveform, R_fixture 50.000, V_fixture 0.0: 20-80 % time 155ps typ, 184ps min, 141ps max; typ from 0 V to 0.473 V
|   rising waveform, R_fixture 50.000, V_fixture 0.600: 20-80 % time 135ps typ, 158ps min, 122ps max; typ from 0.358 V to 0.84 V
|   falling waveform, R_fixture 50.000, V_fixture 0.600: 20-80 % time 119ps typ, 142ps min, 109ps max; typ from 0.84 V to 0.358 V
|   falling waveform, R_fixture 50.000, V_fixture 0.0: 20-80 % time 114ps typ, 134ps min, 105ps max; typ from 0.473 V to 0 V
[Pulldown]
|Voltage   I(typ)   I(min)   I(max)
-1.2V     -126.6mA   -141.6mA   -119.6mA
-1.089V   -69.94mA   -83.01mA   -66.44mA
-978mV    -42.76mA   -46.49mA   -46.39mA
-867mV    -31.24mA   -30.49mA   -34.94mA
-645mV    -14.34mA   -14.52mA   -15.2mA
-423mV    -5.85mA    -6.033mA   -5.472mA
1.575V    20.81mA    20.49mA    19.96mA
2.019V    35.02mA    36.94mA    35.75mA
2.13V     41.9mA     57.64mA    41.37mA
2.241V    65.57mA    104.5mA    50.12mA
2.315V    100.4mA    147.6mA    69.01mA
2.4V      153.4mA    203.7mA    113.3mA
[Pullup]
|Voltage   I(typ)   I(min)   I(max)
-1.2V     147.7mA    170.9mA    134.1mA
-1.115V   92.54mA    116.5mA    78.56mA
-1.041V   54.38mA    75.84mA    43.86mA
-967mV    31.49mA    45.22mA    28.65mA
-856mV    20.02mA    21.93mA    21.77mA
-338mV    4.624mA    4.426mA    4.313mA
1.586V    -17.93mA   -17.3mA    -16.9mA
1.845V    -25.39mA   -26.75mA   -23.15mA
2.067V    -41.23mA   -43.42mA   -40.69mA
2.178V    -51.9mA    -63.39mA   -51.24mA
2.289V    -76.33mA   -106.6mA   -64.55mA
2.4V      -130.6mA   -169.4mA   -101.3mA
[Ramp]
| variable   typ   min   max
dV/dt_r   0.284/0.155n   0.263/0.184n   0.282/0.141n
dV/dt_f   0.290/0.134n   0.277/0.164n   0.289/0.120n
R_load = 50.000
[Rising Waveform]
R_fixture= 50.000
V_fixture= 0.0
V_fixture_min= 0.0
V_fixture_max= 0.0
|time   V(typ)   V(min)   V(max)
0s        1.7uV      9.144uV    771nV
393ps     190.4uV    115.8uV    64.65uV
431ps     -250.6uV   215.1uV    49.76mV
500ps     1.622mV    -219.3uV   213.2mV
608ps     195.7mV    5.888mV    393.5mV
692ps     350mV      114.8mV    442mV
859ps     452.6mV    349.8mV    466.4mV
1.028ns   469.4mV    418.6mV    469.8mV
1.372ns   472.7mV    436.4mV    470.5mV
10ns      472.9mV    437.5mV    470.5mV
[Rising Waveform]
R_fixture= 50.000
V_fixture= 0.600
V_fixture_min= 0.583
V_fixture_max= 0.619
|time   V(typ)   V(min)   V(max)
0s        357.8mV    350mV      378mV
401ps     357.9mV    350.1mV    379.7mV
500ps     363.7mV    349.8mV    591.1mV
551ps     429.6mV    350.3mV    718.8mV
612ps     575.4mV    364.8mV    795.3mV
700ps     747.3mV    494.8mV    837.7mV
829ps     820.6mV    713.5mV    853.9mV
989ps     837.2mV    786.9mV    857.4mV
1.318ns   840.3mV    803.6mV    858mV
10ns      840.5mV    804.5mV    858mV
[Falling Waveform]
R_fixture= 50.000
V_fixture= 0.600
V_fixture_min= 0.583
V_fixture_max= 0.619
|time   V(typ)   V(min)   V(max)
0s        840.5mV    804.5mV    858mV
400ps     840.7mV    804.6mV    856.3mV
435ps     841.7mV    804.6mV    799.3mV
502ps     835.3mV    805.6mV    581.6mV
596ps     619.2mV    797.4mV    435.3mV
662ps     471.1mV    709.4mV    403mV
807ps     377.8mV    435.8mV    382.8mV
957ps     362.3mV    368.2mV    379.1mV
1.267ns   358.3mV    351.9mV    378.1mV
10ns      357.8mV    350mV      378mV
[Falling Waveform]
R_fixture= 50.000
V_fixture= 0.0
V_fixture_min= 0.0
V_fixture_max= 0.0
|time   V(typ)   V(min)   V(max)
0s        472.9mV    437.5mV    470.5mV
395ps     473.4mV    437.6mV    468.7mV
427ps     474.3mV    437.7mV    417.7mV
489ps     469.1mV    438.9mV    212.2mV
553ps     342.8mV    438.4mV    84.51mV
643ps     111.5mV    346.5mV    24.97mV
787ps     16.72mV    74.93mV    4.232mV
917ps     3.74mV     15.08mV    1.067mV
1.247ns   270uV      748.1uV    100.1uV
10ns      1.716uV    9.154uV    790.9nV
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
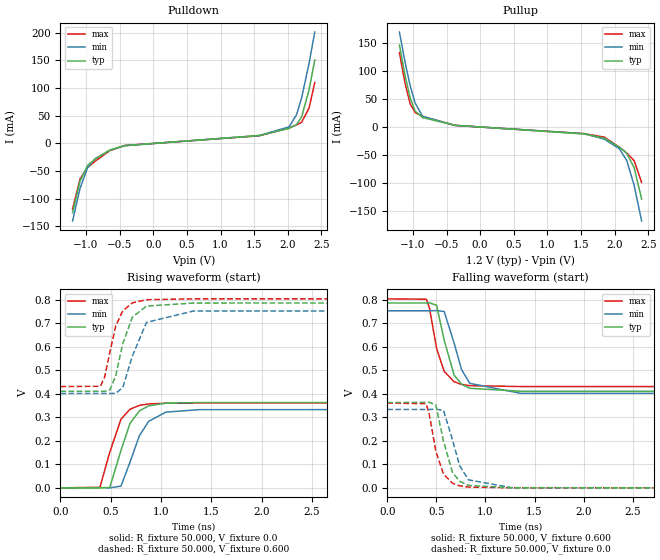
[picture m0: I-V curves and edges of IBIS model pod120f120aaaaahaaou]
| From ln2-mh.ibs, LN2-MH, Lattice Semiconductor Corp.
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|   Model pod120f120aaaaahaaou
[Model] pod120f120aaaaahaaou
Model_type Output
Polarity   Non-Inverting
Enable   Active-High
Vmeas =  0.600V
Cref =  20.000pF
Rref =  50.000
Vref =  0.600V
C_comp   2.000pF   1.500pF   2.500pF
[Temperature Range]   25.000   0.125k   -40.000
[Voltage Range]   1.200V   1.160V   1.240V
[C Comp Corner]
C_comp   2.000pF   1.500pF   2.500pF
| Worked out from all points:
|   slope of the pulldown table from 0 to 0.18 V, typ, clamps not added: 108 ohm
|   slope of the pullup table from 0 to 0.18 V, typ, clamps not added: 110 ohm
|   rising waveform, R_fixture 50.000, V_fixture 0.0: 20-80 % time 163ps typ, 186ps min, 152ps max; typ from 0 V to 0.363 V
|   rising waveform, R_fixture 50.000, V_fixture 0.600: 20-80 % time 140ps typ, 159ps min, 128ps max; typ from 0.411 V to 0.787 V
|   falling waveform, R_fixture 50.000, V_fixture 0.600: 20-80 % time 130ps typ, 148ps min, 121ps max; typ from 0.787 V to 0.411 V
|   falling waveform, R_fixture 50.000, V_fixture 0.0: 20-80 % time 123ps typ, 138ps min, 117ps max; typ from 0.363 V to 0 V
[Pulldown]
|Voltage   I(typ)   I(min)   I(max)
-1.2V     -125.3mA   -140.3mA   -118.5mA
-1.089V   -68.01mA   -81.31mA   -64.45mA
-978mV    -40.12mA   -44.17mA   -43.91mA
-867mV    -28.57mA   -27.93mA   -32.53mA
-645mV    -11.95mA   -12.2mA    -13.02mA
-423mV    -4.023mA   -4.255mA   -3.77mA
1.575V    14.23mA    14.15mA    13.66mA
2.019V    27.14mA    29.91mA    28.05mA
2.13V     34.19mA    52.06mA    33.31mA
2.204V    47.64mA    81.78mA    38.11mA
2.315V    96.57mA    144.6mA    63.67mA
2.4V      150.6mA    201.2mA    110mA
[Pullup]
|Voltage   I(typ)   I(min)   I(max)
-1.2V     146.8mA    170mA      133.3mA
-1.115V   91.35mA    115.4mA    77.46mA
-1.041V   52.71mA    74.45mA    42.14mA
-967mV    29.22mA    43.42mA    26.38mA
-856mV    17.44mA    19.64mA    19.45mA
-375mV    3.626mA    3.534mA    3.469mA
1.549V    -11.88mA   -11.38mA   -11.25mA
1.845V    -19.34mA   -21.07mA   -17.49mA
2.067V    -35.24mA   -37.99mA   -35.13mA
2.178V    -46.18mA   -58.97mA   -45.72mA
2.289V    -72.18mA   -103.6mA   -59.52mA
2.4V      -128mA     -167.1mA   -98.35mA
[Ramp]
| variable   typ   min   max
dV/dt_r   0.218/0.163n   0.200/0.186n   0.217/0.152n
dV/dt_f   0.226/0.144n   0.215/0.170n   0.225/0.132n
R_load = 50.000
[Rising Waveform]
R_fixture= 50.000
V_fixture= 0.0
V_fixture_min= 0.0
V_fixture_max= 0.0
|time   V(typ)   V(min)   V(max)
0s        1.991uV    10.66uV    896.8nV
393ps     225.8uV    129.8uV    2.314mV
490ps     1.098mV    -22.6uV    151mV
602ps     159.5mV    7.393mV    292.2mV
691ps     273.5mV    108.4mV    334.2mV
785ps     327.8mV    221.8mV    351.1mV
877ps     349mV      282.8mV    357.2mV
1.047ns   360.5mV    322.1mV    360.2mV
1.377ns   363mV      332.8mV    360.9mV
10ns      363.2mV    333.6mV    360.9mV
[Rising Waveform]
R_fixture= 50.000
V_fixture= 0.600
V_fixture_min= 0.583
V_fixture_max= 0.619
|time   V(typ)   V(min)   V(max)
0s        411mV      401.5mV    431.1mV
398ps     411.1mV    401.6mV    432.3mV
440ps     411.1mV    401.7mV    472.7mV
491ps     416.4mV    401.5mV    575.8mV
549ps     475.3mV    402.2mV    687.8mV
620ps     613.9mV    426.6mV    753.5mV
715ps     726.4mV    560.7mV    787.4mV
856ps     773.8mV    704.4mV    800.9mV
1.325ns   786.6mV    752.9mV    804.4mV
10ns      786.8mV    753.6mV    804.4mV
[Falling Waveform]
R_fixture= 50.000
V_fixture= 0.600
V_fixture_min= 0.583
V_fixture_max= 0.619
|time   V(typ)   V(min)   V(max)
0s        786.8mV    753.6mV    804.4mV
398ps     787mV      753.6mV    802.9mV
430ps     787.6mV    753.6mV    764.2mV
502ps     776.8mV    754.4mV    593.1mV
579ps     629.2mV    750.6mV    495.8mV
680ps     480.4mV    616.9mV    451.7mV
756ps     441.3mV    503.3mV    440.2mV
840ps     423.8mV    444.8mV    435mV
1.357ns   411.2mV    402.4mV    431.2mV
10ns      411mV      401.5mV    431.1mV
[Falling Waveform]
R_fixture= 50.000
V_fixture= 0.0
V_fixture_min= 0.0
V_fixture_max= 0.0
|time   V(typ)   V(min)   V(max)
0s        363.1mV    333.6mV    360.9mV
395ps     363.7mV    333.6mV    358.1mV
427ps     364.3mV    333.7mV    314.4mV
494ps     352.9mV    334.8mV    156.3mV
572ps     199.1mV    329.8mV    58.87mV
663ps     66.29mV    205.6mV    20.01mV
736ps     28.34mV    95.28mV    8.738mV
827ps     10.35mV    34.08mV    3.265mV
1.267ns   234.9uV    632.7uV    92.37uV
10ns      2.007uV    10.68uV    917.3nV
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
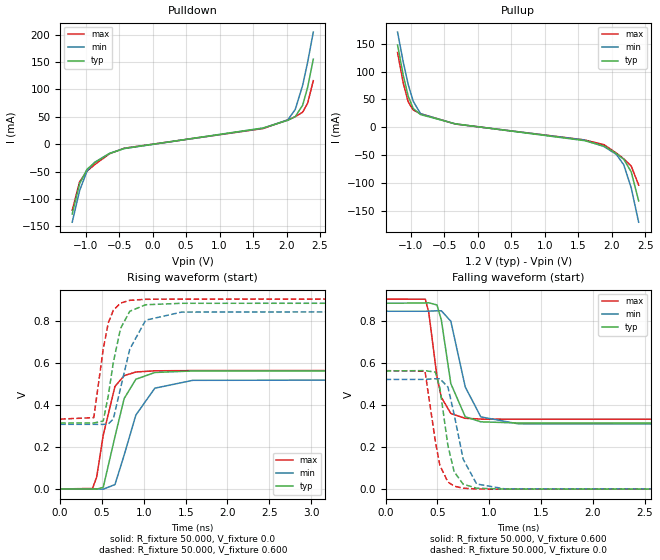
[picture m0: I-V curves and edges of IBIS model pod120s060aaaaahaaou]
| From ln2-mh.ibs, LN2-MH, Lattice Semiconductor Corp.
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|   Model pod120s060aaaaahaaou
[Model] pod120s060aaaaahaaou
Model_type Output
Polarity   Non-Inverting
Enable   Active-High
Vmeas =  0.600V
Cref =  20.000pF
Rref =  50.000
Vref =  0.600V
C_comp   2.000pF   1.500pF   2.500pF
[Temperature Range]   25.000   0.125k   -40.000
[Voltage Range]   1.200V   1.160V   1.240V
[C Comp Corner]
C_comp   2.000pF   1.500pF   2.500pF
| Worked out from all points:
|   slope of the pulldown table from 0 to 0.18 V, typ, clamps not added: 54.8 ohm
|   slope of the pullup table from 0 to 0.18 V, typ, clamps not added: 55.5 ohm
|   rising waveform, R_fixture 50.000, V_fixture 0.0: 20-80 % time 191ps typ, 255ps min, 156ps max; typ from 0 V to 0.562 V
|   rising waveform, R_fixture 50.000, V_fixture 0.600: 20-80 % time 158ps typ, 212ps min, 127ps max; typ from 0.314 V to 0.884 V
|   falling waveform, R_fixture 50.000, V_fixture 0.600: 20-80 % time 116ps typ, 151ps min, 102ps max; typ from 0.884 V to 0.314 V
|   falling waveform, R_fixture 50.000, V_fixture 0.0: 20-80 % time 108ps typ, 135ps min, 99.9ps max; typ from 0.562 V to 0 V
[Pulldown]
|Voltage   I(typ)   I(min)   I(max)
-1.2V     -127.6mA   -142.5mA   -120.7mA
-1.089V   -71.86mA   -84.58mA   -68.57mA
-978mV    -45.57mA   -48.89mA   -49.13mA
-867mV    -34.1mA    -33.22mA   -37.62mA
-645mV    -16.91mA   -17.02mA   -17.62mA
-423mV    -7.819mA   -7.942mA   -7.369mA
1.649V    29.6mA     29.08mA    28.54mA
2.019V    43.56mA    44.45mA    44.25mA
2.13V     50.29mA    63.23mA    50.23mA
2.241V    71.16mA    107.5mA    58.54mA
2.315V    103.7mA    149.5mA    74.75mA
2.4V      155.2mA    204.8mA    116mA
[Pullup]
|Voltage   I(typ)   I(min)   I(max)
-1.2V     148.2mA    171.3mA    134.6mA
-1.115V   93.42mA    117.2mA    79.51mA
-1.041V   55.91mA    76.92mA    45.64mA
-967mV    33.83mA    46.87mA    31.12mA
-856mV    22.76mA    24.27mA    24.31mA
-338mV    6.161mA    5.836mA    5.775mA
1.586V    -24.03mA   -22.97mA   -22.74mA
1.882V    -33.88mA   -34.76mA   -31.47mA
2.067V    -47.43mA   -48.94mA   -46.55mA
2.178V    -57.8mA    -67.71mA   -57.04mA
2.289V    -80.43mA   -109.2mA   -69.86mA
2.4V      -132.7mA   -171mA     -104.2mA
[Ramp]
| variable   typ   min   max
dV/dt_r   0.337/0.192n   0.313/0.255n   0.338/0.157n
dV/dt_f   0.343/0.133n   0.328/0.184n   0.344/0.106n
R_load = 50.000
[Rising Waveform]
R_fixture= 50.000
V_fixture= 0.0
V_fixture_min= 0.0
V_fixture_max= 0.0
|time   V(typ)   V(min)   V(max)
0s        1.465uV    7.91uV     665.2nV
387ps     -61.4uV    68.67uV    2.486mV
437ps     -912.6uV   65.15uV    57.4mV
515ps     7.77mV     -873.1uV   256.1mV
655ps     248.6mV    20.79mV    487.9mV
765ps     430.3mV    161.1mV    539.1mV
905ps     522mV      351.8mV    556.6mV
1.132ns   554.2mV    479.5mV    562.2mV
1.585ns   561.5mV    516.9mV    563.2mV
10ns      562.1mV    521.7mV    563.3mV
[Rising Waveform]
R_fixture= 50.000
V_fixture= 0.600
V_fixture_min= 0.583
V_fixture_max= 0.619
|time   V(typ)   V(min)   V(max)
0s        314mV      307.6mV    332.3mV
402ps     313.7mV    307.6mV    339.5mV
515ps     323.6mV    307.3mV    665.3mV
575ps     443.5mV    309.2mV    789.6mV
636ps     603mV      333.6mV    850.5mV
722ps     763.8mV    480.1mV    884.3mV
832ps     845.5mV    665mV      897.5mV
1.022ns   876.4mV    803mV      902.4mV
1.452ns   883.4mV    841.6mV    903.5mV
10ns      883.9mV    845.6mV    903.5mV
[Falling Waveform]
R_fixture= 50.000
V_fixture= 0.600
V_fixture_min= 0.583
V_fixture_max= 0.619
|time   V(typ)   V(min)   V(max)
0s        883.9mV    845.6mV    903.5mV
384ps     884.6mV    845.6mV    902.7mV
417ps     886mV      845.9mV    840.8mV
497ps     875.3mV    847.8mV    532.4mV
539ps     802.7mV    847.7mV    436.1mV
630ps     501.6mV    798.2mV    359.8mV
769ps     344.1mV    486.1mV    336.9mV
919ps     320.1mV    343.6mV    333.2mV
1.279ns   314.5mV    310.6mV    332.3mV
10ns      314mV      307.6mV    332.3mV
[Falling Waveform]
R_fixture= 50.000
V_fixture= 0.0
V_fixture_min= 0.0
V_fixture_max= 0.0
|time   V(typ)   V(min)   V(max)
0s        562mV      521.7mV    563.2mV
381ps     563.4mV    521.8mV    561.1mV
481ps     556.1mV    524.7mV    227mV
524ps     481.9mV    524.8mV    113.6mV
602ps     207.2mV    485.6mV    34mV
662ps     83.05mV    355.7mV    14.3mV
749ps     23.61mV    142.6mV    4.45mV
879ps     4.564mV    24.65mV    955.9uV
1.149ns   393.2uV    1.543mV    90.73uV
10ns      1.484uV    7.927uV    686.9nV
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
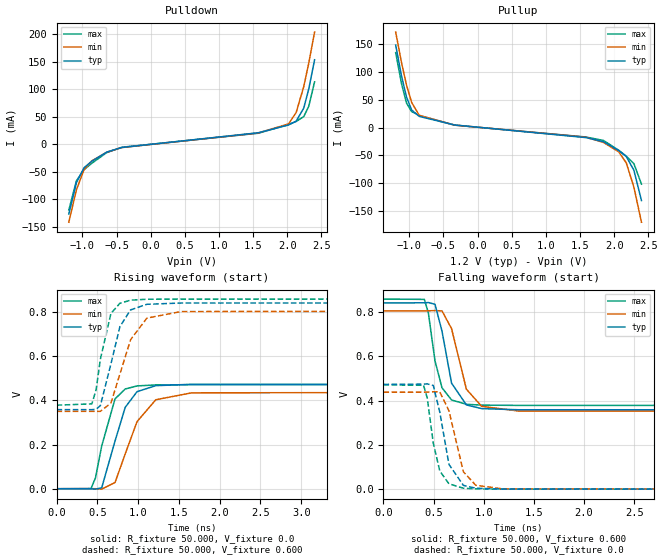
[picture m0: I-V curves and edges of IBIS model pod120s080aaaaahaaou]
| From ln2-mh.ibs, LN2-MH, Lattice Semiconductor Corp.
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|   Model pod120s080aaaaahaaou
[Model] pod120s080aaaaahaaou
Model_type Output
Polarity   Non-Inverting
Enable   Active-High
Vmeas =  0.600V
Cref =  20.000pF
Rref =  50.000
Vref =  0.600V
C_comp   2.000pF   1.500pF   2.500pF
[Temperature Range]   25.000   0.125k   -40.000
[Voltage Range]   1.200V   1.160V   1.240V
[C Comp Corner]
C_comp   2.000pF   1.500pF   2.500pF
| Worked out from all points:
|   slope of the pulldown table from 0 to 0.18 V, typ, clamps not added: 73.8 ohm
|   slope of the pullup table from 0 to 0.18 V, typ, clamps not added: 74.4 ohm
|   rising waveform, R_fixture 50.000, V_fixture 0.0: 20-80 % time 213ps typ, 278ps min, 172ps max; typ from 0 V to 0.473 V
|   rising waveform, R_fixture 50.000, V_fixture 0.600: 20-80 % time 176ps typ, 237ps min, 136ps max; typ from 0.358 V to 0.84 V
|   falling waveform, R_fixture 50.000, V_fixture 0.600: 20-80 % time 125ps typ, 152ps min, 110ps max; typ from 0.84 V to 0.358 V
|   falling waveform, R_fixture 50.000, V_fixture 0.0: 20-80 % time 114ps typ, 134ps min, 104ps max; typ from 0.473 V to 0 V
[Pulldown]
|Voltage   I(typ)   I(min)   I(max)
-1.2V     -126.6mA   -141.6mA   -119.6mA
-1.089V   -69.94mA   -83.01mA   -66.44mA
-978mV    -42.76mA   -46.49mA   -46.39mA
-867mV    -31.24mA   -30.49mA   -34.94mA
-645mV    -14.34mA   -14.52mA   -15.2mA
-423mV    -5.85mA    -6.032mA   -5.472mA
1.575V    20.81mA    20.49mA    19.96mA
2.019V    35.02mA    36.94mA    35.75mA
2.13V     41.9mA     57.64mA    41.37mA
2.241V    65.57mA    104.5mA    50.12mA
2.315V    100.4mA    147.6mA    69.01mA
2.4V      153.4mA    203.7mA    113.3mA
[Pullup]
|Voltage   I(typ)   I(min)   I(max)
-1.2V     147.7mA    170.9mA    134.1mA
-1.115V   92.54mA    116.5mA    78.56mA
-1.041V   54.38mA    75.84mA    43.86mA
-967mV    31.49mA    45.22mA    28.65mA
-856mV    20.02mA    21.93mA    21.77mA
-338mV    4.624mA    4.426mA    4.313mA
1.586V    -17.93mA   -17.3mA    -16.9mA
1.845V    -25.39mA   -26.75mA   -23.15mA
2.067V    -41.23mA   -43.42mA   -40.69mA
2.178V    -51.9mA    -63.39mA   -51.24mA
2.289V    -76.33mA   -106.6mA   -64.55mA
2.4V      -130.6mA   -169.4mA   -101.3mA
[Ramp]
| variable   typ   min   max
dV/dt_r   0.284/0.212n   0.263/0.278n   0.282/0.173n
dV/dt_f   0.290/0.144n   0.277/0.184n   0.289/0.124n
R_load = 50.000
[Rising Waveform]
R_fixture= 50.000
V_fixture= 0.0
V_fixture_min= 0.0
V_fixture_max= 0.0
|time   V(typ)   V(min)   V(max)
0s        1.7uV      9.144uV    771nV
423ps     -243.4uV   199.3uV    1.132mV
477ps     -1.999mV   29.05uV    48.37mV
554ps     4.577mV    -1.549mV   193.6mV
717ps     215.6mV    27.82mV    406.4mV
842ps     368.1mV    157.5mV    451.1mV
987ps     439.2mV    303.7mV    465.1mV
1.217ns   466.3mV    402.6mV    469.6mV
1.657ns   472.4mV    433.8mV    470.5mV
10ns      472.9mV    437.5mV    470.5mV
[Rising Waveform]
R_fixture= 50.000
V_fixture= 0.600
V_fixture_min= 0.583
V_fixture_max= 0.619
|time   V(typ)   V(min)   V(max)
0s        357.8mV    350mV      378mV
433ps     357.6mV    350.2mV    383.8mV
485ps     359.3mV    349.9mV    447.5mV
538ps     376.4mV    350.1mV    586.8mV
667ps     564.8mV    387.5mV    793.1mV
777ps     733.4mV    518.7mV    839mV
907ps     808.8mV    673.7mV    853mV
1.107ns   834.4mV    771.8mV    857.2mV
1.527ns   840.1mV    801.5mV    858mV
10ns      840.5mV    804.5mV    858mV
[Falling Waveform]
R_fixture= 50.000
V_fixture= 0.600
V_fixture_min= 0.583
V_fixture_max= 0.619
|time   V(typ)   V(min)   V(max)
0s        840.5mV    804.5mV    858mV
408ps     841.1mV    804.6mV    856.6mV
448ps     842.2mV    804.9mV    795.4mV
514ps     834.6mV    806mV      579.5mV
584ps     713.1mV    804.5mV    457.6mV
679ps     478.6mV    724.6mV    402.6mV
827ps     380.3mV    451.2mV    383mV
979ps     363.5mV    373.9mV    379.3mV
1.347ns   358.4mV    352.6mV    378.1mV
10ns      357.8mV    350mV      378mV
[Falling Waveform]
R_fixture= 50.000
V_fixture= 0.0
V_fixture_min= 0.0
V_fixture_max= 0.0
|time   V(typ)   V(min)   V(max)
0s        472.9mV    437.5mV    470.5mV
400ps     474.1mV    437.6mV    469.2mV
437ps     475.2mV    438.1mV    411.2mV
497ps     468.1mV    439.7mV    207.8mV
562ps     347.4mV    439.2mV    82.04mV
653ps     112mV      353.9mV    24.14mV
797ps     17.13mV    78.54mV    4.167mV
920ps     4.216mV    17.56mV    1.159mV
1.191ns   465.7uV    1.356mV    159.9uV
10ns      1.716uV    9.154uV    791.4nV
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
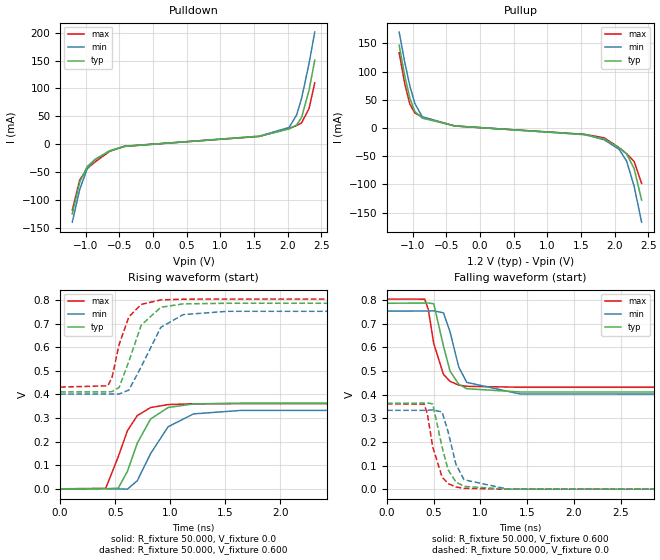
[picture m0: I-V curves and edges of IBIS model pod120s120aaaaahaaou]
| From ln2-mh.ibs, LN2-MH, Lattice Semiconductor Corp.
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|   Model pod120s120aaaaahaaou
[Model] pod120s120aaaaahaaou
Model_type Output
Polarity   Non-Inverting
Enable   Active-High
Vmeas =  0.600V
Cref =  20.000pF
Rref =  50.000
Vref =  0.600V
C_comp   2.000pF   1.500pF   2.500pF
[Temperature Range]   25.000   0.125k   -40.000
[Voltage Range]   1.200V   1.160V   1.240V
[C Comp Corner]
C_comp   2.000pF   1.500pF   2.500pF
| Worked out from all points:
|   slope of the pulldown table from 0 to 0.18 V, typ, clamps not added: 108 ohm
|   slope of the pullup table from 0 to 0.18 V, typ, clamps not added: 110 ohm
|   rising waveform, R_fixture 50.000, V_fixture 0.0: 20-80 % time 202ps typ, 251ps min, 175ps max; typ from 0 V to 0.363 V
|   rising waveform, R_fixture 50.000, V_fixture 0.600: 20-80 % time 164ps typ, 211ps min, 137ps max; typ from 0.411 V to 0.787 V
|   falling waveform, R_fixture 50.000, V_fixture 0.600: 20-80 % time 132ps typ, 154ps min, 121ps max; typ from 0.787 V to 0.411 V
|   falling waveform, R_fixture 50.000, V_fixture 0.0: 20-80 % time 123ps typ, 138ps min, 116ps max; typ from 0.363 V to 0 V
[Pulldown]
|Voltage   I(typ)   I(min)   I(max)
-1.2V     -125.3mA   -140.3mA   -118.5mA
-1.089V   -68.01mA   -81.31mA   -64.45mA
-978mV    -40.12mA   -44.17mA   -43.91mA
-867mV    -28.57mA   -27.93mA   -32.53mA
-645mV    -11.95mA   -12.2mA    -13.02mA
-423mV    -4.023mA   -4.255mA   -3.77mA
1.575V    14.23mA    14.15mA    13.66mA
2.019V    27.14mA    29.91mA    28.05mA
2.13V     34.19mA    52.06mA    33.31mA
2.204V    47.64mA    81.78mA    38.11mA
2.315V    96.57mA    144.6mA    63.67mA
2.4V      150.6mA    201.2mA    110mA
[Pullup]
|Voltage   I(typ)   I(min)   I(max)
-1.2V     146.8mA    170mA      133.3mA
-1.115V   91.35mA    115.4mA    77.46mA
-1.041V   52.71mA    74.45mA    42.14mA
-967mV    29.22mA    43.42mA    26.38mA
-856mV    17.44mA    19.64mA    19.45mA
-375mV    3.626mA    3.534mA    3.469mA
1.549V    -11.88mA   -11.38mA   -11.25mA
1.845V    -19.34mA   -21.07mA   -17.49mA
2.067V    -35.24mA   -37.99mA   -35.13mA
2.178V    -46.18mA   -58.97mA   -45.72mA
2.289V    -72.18mA   -103.6mA   -59.52mA
2.4V      -128mA     -167.1mA   -98.35mA
[Ramp]
| variable   typ   min   max
dV/dt_r   0.218/0.202n   0.200/0.250n   0.217/0.175n
dV/dt_f   0.226/0.151n   0.215/0.184n   0.225/0.134n
R_load = 50.000
[Rising Waveform]
R_fixture= 50.000
V_fixture= 0.0
V_fixture_min= 0.0
V_fixture_max= 0.0
|time   V(typ)   V(min)   V(max)
0s        1.991uV    10.66uV    896.8nV
413ps     9.082uV    181.7uV    2.024mV
528ps     3.028mV    -438uV     136.6mV
611ps     74.21mV    -1.511mV   246.5mV
701ps     194mV      34.66mV    310.7mV
821ps     295.9mV    149.3mV    344.5mV
981ps     344.7mV    263.3mV    357.1mV
1.211ns   360mV      317.6mV    360.4mV
1.637ns   363mV      332.2mV    360.9mV
10ns      363.1mV    333.6mV    360.9mV
[Rising Waveform]
R_fixture= 50.000
V_fixture= 0.600
V_fixture_min= 0.583
V_fixture_max= 0.619
|time   V(typ)   V(min)   V(max)
0s        411mV      401.5mV    431.1mV
434ps     411mV      401.7mV    436.7mV
472ps     412.1mV    401.6mV    473.8mV
535ps     429.6mV    401.7mV    610.8mV
624ps     540.3mV    418.7mV    729mV
736ps     694mV      517.2mV    781.8mV
914ps     769.5mV    684.4mV    800.8mV
1.117ns   783.9mV    738.5mV    803.9mV
1.516ns   786.6mV    752.4mV    804.4mV
10ns      786.8mV    753.6mV    804.4mV
[Falling Waveform]
R_fixture= 50.000
V_fixture= 0.600
V_fixture_min= 0.583
V_fixture_max= 0.619
|time   V(typ)   V(min)   V(max)
0s        786.8mV    753.6mV    804.4mV
403ps     787.3mV    753.7mV    804mV
441ps     788.1mV    753.8mV    761.7mV
500ps     784.4mV    754.7mV    616mV
604ps     605.5mV    746mV      485.7mV
674ps     500mV      666.4mV    456.1mV
767ps     444mV      517.2mV    440.5mV
853ps     425mV      451.8mV    435.2mV
1.427ns   411.2mV    402.6mV    431.2mV
10ns      411mV      401.5mV    431.1mV
[Falling Waveform]
R_fixture= 50.000
V_fixture= 0.0
V_fixture_min= 0.0
V_fixture_max= 0.0
|time   V(typ)   V(min)   V(max)
0s        363.1mV    333.6mV    360.9mV
397ps     364.2mV    333.6mV    359.9mV
432ps     365.1mV    334mV      317.7mV
489ps     360.9mV    335.5mV    178.7mV
589ps     178.8mV    326.8mV    51.4mV
653ps     82.09mV    243.7mV    24.07mV
737ps     30.79mV    105.5mV    9.256mV
824ps     11.73mV    39.77mV    3.614mV
1.287ns   239.3uV    652.6uV    90.73uV
10ns      2.007uV    10.68uV    917.6nV
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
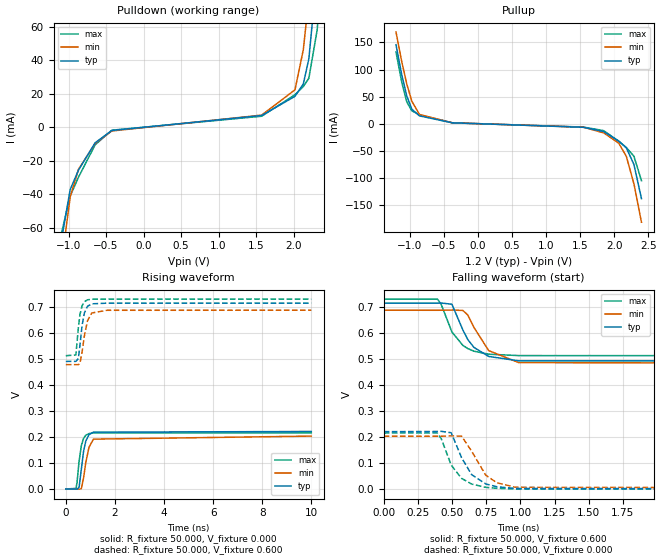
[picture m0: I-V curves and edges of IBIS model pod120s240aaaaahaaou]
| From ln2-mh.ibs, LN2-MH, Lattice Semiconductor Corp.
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|   Model pod120s240aaaaahaaou
[Model] pod120s240aaaaahaaou
Model_type Output
Polarity   Non-Inverting
Enable   Active-High
Vmeas =  0.600V
Cref =  20.000pF
Rref =  50.000
Vref =  0.600V
C_comp   2.000pF   1.500pF   2.500pF
[Temperature Range]   25.000   0.125k   -40.000
[Voltage Range]   1.200V   1.160V   1.240V
[C Comp Corner]
C_comp   2.000pF   1.500pF   2.500pF
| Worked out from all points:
|   slope of the pulldown table from 0 to 0.18 V, typ, clamps not added: 226 ohm
|   slope of the pullup table from 0 to 0.18 V, typ, clamps not added: 206 ohm
|   rising waveform, R_fixture 50.000, V_fixture 0.000: 20-80 % time 194ps typ, 233ps min, 171ps max; typ from 0 V to 0.221 V
|   rising waveform, R_fixture 50.000, V_fixture 0.600: 20-80 % time 180ps typ, 225ps min, 153ps max; typ from 0.492 V to 0.716 V
|   falling waveform, R_fixture 50.000, V_fixture 0.600: 20-80 % time 141ps typ, 158ps min, 133ps max; typ from 0.716 V to 0.492 V
|   falling waveform, R_fixture 50.000, V_fixture 0.000: 20-80 % time 135ps typ, 146ps min, 130ps max; typ from 0.221 V to 0 V
[Pulldown]
|Voltage   I(typ)   I(min)   I(max)
-1.2V     -124mA     -138.9mA   -117.2mA
-1.089V   -65.9mA    -79.46mA   -62.24mA
-978mV    -37.23mA   -41.63mA   -41.1mA
-867mV    -25.63mA   -25.11mA   -29.79mA
-645mV    -9.312mA   -9.639mA   -10.55mA
-423mV    -2.006mA   -2.297mA   -1.829mA
1.575V    6.943mA    7.179mA    6.507mA
2.019V    18.39mA    22.25mA    19.32mA
2.13V     25.73mA    46.11mA    24.21mA
2.204V    40.77mA    77.2mA     29.17mA
2.315V    92.48mA    141.3mA    58mA
2.4V      147.6mA    198.5mA    106.6mA
[Pullup]
|Voltage   I(typ)   I(min)   I(max)
-1.2V     145.8mA    169.1mA    132.5mA
-1.115V   90.09mA    114.3mA    76.26mA
-1.041V   50.94mA    72.99mA    40.27mA
-967mV    26.8mA     41.54mA    23.88mA
-856mV    14.66mA    17.23mA    16.88mA
-375mV    1.899mA    1.955mA    1.838mA
1.549V    -6.379mA   -6.274mA   -5.964mA
1.845V    -14.26mA   -16.65mA   -12.54mA
2.067V    -31.83mA   -35.61mA   -32.09mA
2.178V    -44.25mA   -59.91mA   -43.81mA
2.289V    -74.74mA   -110.4mA   -59.66mA
2.4V      -137.8mA   -181.3mA   -104.8mA
[Ramp]
| variable   typ   min   max
dV/dt_r   0.133/0.194n   0.122/0.233n   0.130/0.171n
dV/dt_f   0.129/0.155n   0.123/0.183n   0.126/0.142n
R_load = 50.000
[Rising Waveform]
R_fixture = 50.000
V_fixture = 0.000
V_fixture_min = 0.000
V_fixture_max = 0.000
|  time   V(typ)   V(min)   V(max)
0s        2.732uV    13.52uV    1.192uV
417ps     15.33uV    234.2uV    2.044mV
457ps     -847.4uV   288.3uV    24.55mV
541ps     6.076mV    -786.9uV   106.6mV
633ps     75.93mV    1.027mV    166.9mV
723ps     144.6mV    42.68mV    194.6mV
814ps     184.6mV    102.3mV    207mV
947ps     209.5mV    161.2mV    213.5mV
1.126ns   218.8mV    192mV      215.7mV
10ns      221.5mV    203.7mV    216.2mV
[Rising Waveform]
R_fixture = 50.000
V_fixture = 0.600
V_fixture_min = 0.583
V_fixture_max = 0.619
|  time   V(typ)   V(min)   V(max)
0s        491.6mV    479.1mV    513.5mV
410ps     491.7mV    479.3mV    516.5mV
511ps     502.4mV    479.2mV    620.7mV
573ps     550.9mV    482.9mV    670.4mV
665ps     631.6mV    528.8mV    706.9mV
757ps     678.3mV    590.3mV    721.7mV
884ps     704mV      648.5mV    728.9mV
1.056ns   713.5mV    678.1mV    731.3mV
1.676ns   716.1mV    688.7mV    731.9mV
10ns      716.1mV    688.9mV    731.9mV
[Falling Waveform]
R_fixture = 50.000
V_fixture = 0.600
V_fixture_min = 0.583
V_fixture_max = 0.619
|  time   V(typ)   V(min)   V(max)
0s        716.1mV    688.9mV    731.9mV
393ps     716.2mV    688.8mV    731.9mV
420ps     716.6mV    688.9mV    712.1mV
499ps     712mV      689.6mV    605.3mV
579ps     613.2mV    688.1mV    553.6mV
616ps     575.5mV    670.1mV    541.1mV
660ps     545.9mV    623mV      531.2mV
768ps     510.9mV    533.5mV    519.6mV
988ps     494.2mV    487.2mV    514.3mV
10ns      491.6mV    479.1mV    513.5mV
[Falling Waveform]
R_fixture = 50.000
V_fixture = 0.000
V_fixture_min = 0.000
V_fixture_max = 0.000
|  time   V(typ)   V(min)   V(max)
0s        221.5mV    203.7mV    216.2mV
392ps     222mV      203.7mV    216.4mV
421ps     222.7mV    203.8mV    194.5mV
494ps     217.2mV    205.2mV    92.36mV
570ps     120.9mV    204.1mV    41.48mV
644ps     55.61mV    145.6mV    19.54mV
747ps     20.04mV    53.53mV    7.074mV
828ps     9.251mV    24.69mV    3.259mV
963ps     2.69mV     7.259mV    951.5uV
10ns      2.732uV    13.52uV    1.192uV
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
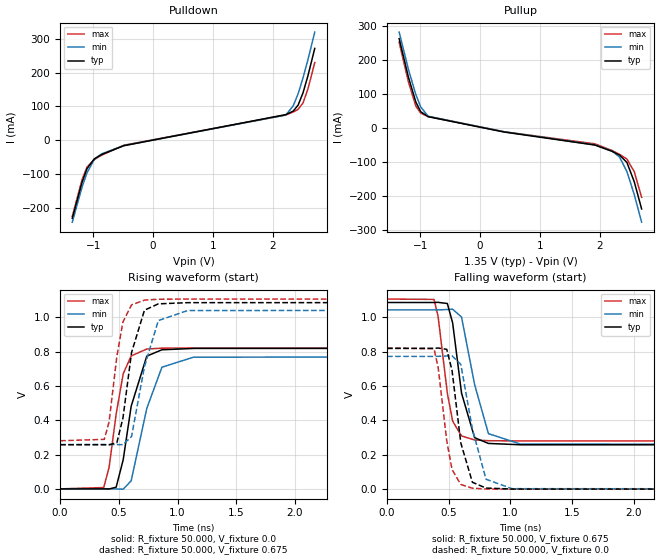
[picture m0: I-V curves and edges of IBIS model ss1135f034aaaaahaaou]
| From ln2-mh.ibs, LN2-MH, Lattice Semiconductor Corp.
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|   Model ss1135f034aaaaahaaou
[Model] ss1135f034aaaaahaaou
Model_type Output
Polarity   Non-Inverting
Enable   Active-High
Vmeas =  0.675V
Cref =  30.000pF
Rref =  50.000
Vref =  0.675V
C_comp   2.000pF   1.500pF   2.500pF
[Temperature Range]   25.000   0.125k   -40.000
[Voltage Range]   1.350V   1.310V   1.390V
[C Comp Corner]
C_comp   2.000pF   1.500pF   2.500pF
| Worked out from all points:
|   slope of the pulldown table from 0 to 0.203 V, typ, clamps not added: 30.8 ohm
|   slope of the pullup table from 0 to 0.203 V, typ, clamps not added: 31.9 ohm
|   rising waveform, R_fixture 50.000, V_fixture 0.0: 20-80 % time 120ps typ, 145ps min, 107ps max; typ from 0 V to 0.82 V
|   rising waveform, R_fixture 50.000, V_fixture 0.675: 20-80 % time 106ps typ, 125ps min, 96.8ps max; typ from 0.258 V to 1.09 V
|   falling waveform, R_fixture 50.000, V_fixture 0.675: 20-80 % time 94.1ps typ, 122ps min, 88.9ps max; typ from 1.09 V to 0.258 V
|   falling waveform, R_fixture 50.000, V_fixture 0.0: 20-80 % time 89.5ps typ, 114ps min, 86.5ps max; typ from 0.82 V to 0 V
[Pulldown]
|Voltage   I(typ)   I(min)   I(max)
-1.35V    -231.2mA   -242.8mA   -225.6mA
-1.186V   -124mA     -138.5mA   -116.4mA
-1.104V   -84.24mA   -96.52mA   -79.52mA
-981mV    -54.97mA   -56.84mA   -57.27mA
-858mV    -42.28mA   -40.3mA    -44.26mA
-489mV    -16.26mA   -15.88mA   -14.89mA
2.217V    75.77mA    74.45mA    74.87mA
2.34V     86.09mA    101.7mA    83.46mA
2.422V    103.9mA    137.5mA    91.31mA
2.504V    140.3mA    184.6mA    110.3mA
2.586V    190.7mA    238.7mA    151.7mA
2.7V      271.8mA    320.2mA    229.8mA
[Pullup]
|Voltage   I(typ)   I(min)   I(max)
-1.35V    261.8mA    281.1mA    251mA
-1.195V   148.5mA    171.6mA    134.6mA
-1.072V   75.84mA    97.64mA    63.81mA
-990mV    47.24mA    61.35mA    42.95mA
-867mV    32.52mA    33.86mA    32.99mA
404mV     -12.56mA   -11.72mA   -11.74mA
1.921V    -50.89mA   -50.12mA   -47.34mA
2.208V    -69.32mA   -68.89mA   -66.82mA
2.331V    -80.1mA    -86.05mA   -78.31mA
2.454V    -102mA     -128.5mA   -91.83mA
2.577V    -158.7mA   -196.4mA   -129.2mA
2.7V      -238.6mA   -277.5mA   -204.4mA
[Ramp]
| variable   typ   min   max
dV/dt_r   0.492/0.120n   0.464/0.146n   0.493/0.107n
dV/dt_f   0.500/0.103n   0.476/0.137n   0.497/92.859p
R_load = 50.000
[Rising Waveform]
R_fixture= 50.000
V_fixture= 0.0
V_fixture_min= 0.0
V_fixture_max= 0.0
|time   V(typ)   V(min)   V(max)
0s        1.101uV    6.191uV    508.8nV
371ps     57.22uV    43.24uV    7.78mV
417ps     -645.6uV   71.12uV    126mV
477ps     9.98mV     -390.2uV   435.8mV
537ps     169.6mV    -1.686mV   671mV
605ps     481.9mV    47.08mV    775.4mV
738ps     774.4mV    469.5mV    815.6mV
867ps     811.2mV    709.7mV    820.6mV
1.136ns   819mV      768.1mV    821.7mV
10ns      819.5mV    773.1mV    821.8mV
[Rising Waveform]
R_fixture= 50.000
V_fixture= 0.675
V_fixture_min= 0.656
V_fixture_max= 0.696
|time   V(typ)   V(min)   V(max)
0s        257.6mV    258.3mV    280.7mV
376ps     257.6mV    258.4mV    288.8mV
417ps     257.1mV    258.4mV    391.4mV
483ps     269.4mV    257.9mV    772.8mV
535ps     413.4mV    258.1mV    973.8mV
608ps     794.8mV    305mV      1.073V
718ps     1.042V     712.8mV    1.101V
836ps     1.079V     981.5mV    1.106V
1.086ns   1.086V     1.04V      1.107V
10ns      1.087V     1.044V     1.107V
[Falling Waveform]
R_fixture= 50.000
V_fixture= 0.675
V_fixture_min= 0.656
V_fixture_max= 0.696
|time   V(typ)   V(min)   V(max)
0s        1.087V     1.044V     1.107V
381ps     1.087V     1.044V     1.105V
414ps     1.088V     1.044V     1.006V
489ps     1.081V     1.046V     558.2mV
532ps     967.7mV    1.048V     396.2mV
604ps     559mV      1.002V     309.9mV
710ps     299.7mV    608.9mV    286.3mV
822ps     266.3mV    323.2mV    282.2mV
1.081ns   258.5mV    262.7mV    280.9mV
10ns      257.6mV    258.3mV    280.7mV
[Falling Waveform]
R_fixture= 50.000
V_fixture= 0.0
V_fixture_min= 0.0
V_fixture_max= 0.0
|time   V(typ)   V(min)   V(max)
0s        819.5mV    773.1mV    821.8mV
381ps     820.1mV    773.2mV    817.8mV
415ps     821.9mV    773.4mV    706.6mV
484ps     814.2mV    775.4mV    282.1mV
527ps     691.8mV    776.6mV    114.2mV
598ps     269.2mV    726.6mV    27.26mV
692ps     40.13mV    350.5mV    5.491mV
802ps     6.469mV    57.96mV    1.22mV
1.012ns   682.5uV    2.899mV    168.7uV
10ns      1.115uV    6.196uV    527.8nV
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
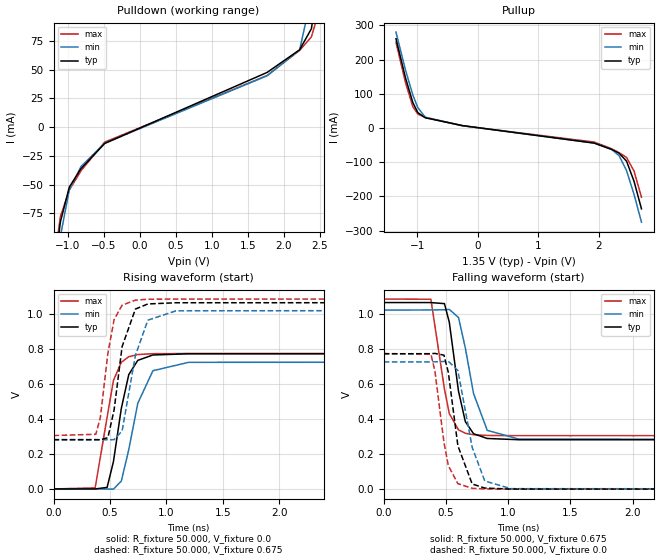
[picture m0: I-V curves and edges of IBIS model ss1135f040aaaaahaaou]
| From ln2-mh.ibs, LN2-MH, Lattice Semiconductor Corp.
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|   Model ss1135f040aaaaahaaou
[Model] ss1135f040aaaaahaaou
Model_type Output
Polarity   Non-Inverting
Enable   Active-High
Vmeas =  0.675V
Cref =  30.000pF
Rref =  50.000
Vref =  0.675V
C_comp   2.000pF   1.500pF   2.500pF
[Temperature Range]   25.000   0.125k   -40.000
[Voltage Range]   1.350V   1.310V   1.390V
[C Comp Corner]
C_comp   2.000pF   1.500pF   2.500pF
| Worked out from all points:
|   slope of the pulldown table from 0 to 0.203 V, typ, clamps not added: 35.6 ohm
|   slope of the pullup table from 0 to 0.203 V, typ, clamps not added: 36.9 ohm
|   rising waveform, R_fixture 50.000, V_fixture 0.0: 20-80 % time 119ps typ, 147ps min, 108ps max; typ from 0 V to 0.771 V
|   rising waveform, R_fixture 50.000, V_fixture 0.675: 20-80 % time 102ps typ, 123ps min, 95.9ps max; typ from 0.281 V to 1.06 V
|   falling waveform, R_fixture 50.000, V_fixture 0.675: 20-80 % time 96.9ps typ, 125ps min, 92.1ps max; typ from 1.06 V to 0.281 V
|   falling waveform, R_fixture 50.000, V_fixture 0.0: 20-80 % time 92.9ps typ, 117ps min, 90.2ps max; typ from 0.771 V to 0 V
[Pulldown]
|Voltage   I(typ)   I(min)   I(max)
-1.35V    -230.2mA   -241.8mA   -224.8mA
-1.186V   -122.6mA   -137.1mA   -115.1mA
-1.104V   -82.23mA   -94.83mA   -77.56mA
-981mV    -52.21mA   -54.48mA   -54.8mA
-817mV    -35.93mA   -34.15mA   -37.8mA
-489mV    -14.19mA   -13.95mA   -13.03mA
1.766V    47.58mA    44.68mA    44.9mA
2.217V    67.27mA    67.18mA    66.71mA
2.381V    85.59mA    113.1mA    78.51mA
2.504V    136mA      181.4mA    104.5mA
2.586V    187.6mA    236.1mA    148.1mA
2.7V      269.4mA    318mA      227.5mA
[Pullup]
|Voltage   I(typ)   I(min)   I(max)
-1.35V    261mA      280.3mA    250.4mA
-1.195V   147.5mA    170.6mA    133.7mA
-1.072V   74.22mA    96.24mA    62.19mA
-990mV    44.92mA    59.51mA    40.66mA
-867mV    29.85mA    31.46mA    30.62mA
-252mV    6.942mA    6.538mA    6.422mA
1.921V    -44.28mA   -43.92mA   -41.11mA
2.208V    -62.72mA   -62.77mA   -60.71mA
2.331V    -73.66mA   -80.81mA   -72.24mA
2.454V    -97.08mA   -124.9mA   -86.13mA
2.577V    -155.8mA   -193.9mA   -125.9mA
2.7V      -236.4mA   -275.4mA   -202.3mA
[Ramp]
| variable   typ   min   max
dV/dt_r   0.463/0.119n   0.435/0.147n   0.464/0.108n
dV/dt_f   0.472/0.106n   0.448/0.141n   0.469/95.342p
R_load = 50.000
[Rising Waveform]
R_fixture= 50.000
V_fixture= 0.0
V_fixture_min= 0.0
V_fixture_max= 0.0
|time   V(typ)   V(min)   V(max)
0s        1.224uV    6.848uV    563.4nV
369ps     63.13uV    47.46uV    6.027mV
475ps     8.79mV     -334.8uV   409.2mV
531ps     155.2mV    -1.249mV   618.4mV
601ps     459.5mV    44.8mV     722.6mV
667ps     652.2mV    224mV      754mV
747ps     733.3mV    488.5mV    766.5mV
881ps     764.1mV    674.3mV    771.4mV
1.197ns   770.9mV    722.1mV    772.4mV
10ns      771.2mV    725.1mV    772.5mV
[Rising Waveform]
R_fixture= 50.000
V_fixture= 0.675
V_fixture_min= 0.656
V_fixture_max= 0.696
|time   V(typ)   V(min)   V(max)
0s        280.9mV    281.2mV    304.7mV
375ps     280.9mV    281.2mV    311.8mV
415ps     280.4mV    281.2mV    407.1mV
482ps     292.6mV    280.8mV    773.9mV
537ps     450.6mV    281.1mV    965.7mV
608ps     811.9mV    331.1mV    1.048V
726ps     1.026V     761.9mV    1.077V
836ps     1.055V     962.5mV    1.082V
1.086ns   1.062V     1.016V     1.083V
10ns      1.063V     1.021V     1.083V
[Falling Waveform]
R_fixture= 50.000
V_fixture= 0.675
V_fixture_min= 0.656
V_fixture_max= 0.696
|time   V(typ)   V(min)   V(max)
0s        1.063V     1.02V      1.083V
379ps     1.063V     1.021V     1.082V
488ps     1.057V     1.022V     570.3mV
527ps     951.3mV    1.024V     430.6mV
601ps     558.5mV    978mV      337.8mV
656ps     384.7mV    804mV      318.5mV
722ps     315.7mV    544.3mV    310mV
832ps     288.8mV    335.1mV    306.1mV
1.085ns   281.6mV    285.3mV    304.9mV
10ns      280.9mV    281.2mV    304.7mV
[Falling Waveform]
R_fixture= 50.000
V_fixture= 0.0
V_fixture_min= 0.0
V_fixture_max= 0.0
|time   V(typ)   V(min)   V(max)
0s        771.2mV    725.1mV    772.5mV
379ps     771.8mV    725.2mV    769.9mV
411ps     773.3mV    725.4mV    674.8mV
484ps     763.5mV    727.4mV    266.5mV
519ps     666.3mV    728.5mV    134.1mV
596ps     247.3mV    676.2mV    31.46mV
711ps     29.48mV    237.9mV    4.877mV
812ps     6.283mV    46.7mV     1.256mV
1.022ns   638.7uV    2.841mV    159.2uV
10ns      1.239uV    6.856uV    582.9nV
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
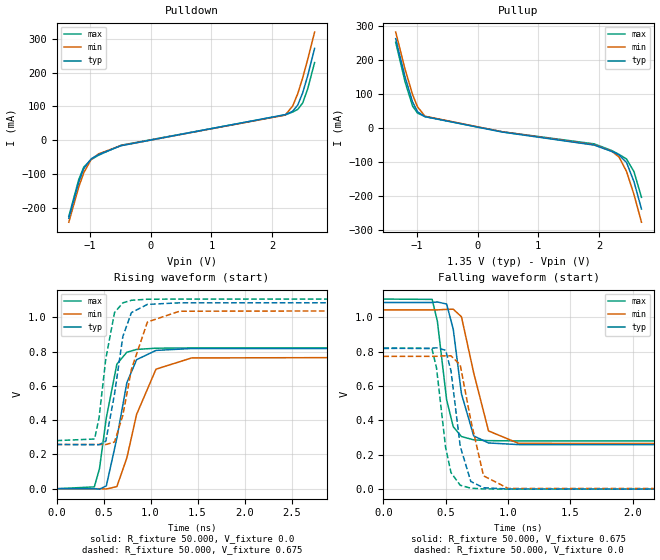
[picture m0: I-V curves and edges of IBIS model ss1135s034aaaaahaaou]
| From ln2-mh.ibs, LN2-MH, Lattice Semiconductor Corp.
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|   Model ss1135s034aaaaahaaou
[Model] ss1135s034aaaaahaaou
Model_type Output
Polarity   Non-Inverting
Enable   Active-High
Vmeas =  0.675V
Cref =  30.000pF
Rref =  50.000
Vref =  0.675V
C_comp   2.000pF   1.500pF   2.500pF
[Temperature Range]   25.000   0.125k   -40.000
[Voltage Range]   1.350V   1.310V   1.390V
[C Comp Corner]
C_comp   2.000pF   1.500pF   2.500pF
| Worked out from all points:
|   slope of the pulldown table from 0 to 0.203 V, typ, clamps not added: 30.8 ohm
|   slope of the pullup table from 0 to 0.203 V, typ, clamps not added: 31.9 ohm
|   rising waveform, R_fixture 50.000, V_fixture 0.0: 20-80 % time 164ps typ, 223ps min, 131ps max; typ from 0 V to 0.82 V
|   rising waveform, R_fixture 50.000, V_fixture 0.675: 20-80 % time 137ps typ, 183ps min, 111ps max; typ from 0.258 V to 1.09 V
|   falling waveform, R_fixture 50.000, V_fixture 0.675: 20-80 % time 95.8ps typ, 124ps min, 85.7ps max; typ from 1.09 V to 0.258 V
|   falling waveform, R_fixture 50.000, V_fixture 0.0: 20-80 % time 88.2ps typ, 111ps min, 82.7ps max; typ from 0.82 V to 0 V
[Pulldown]
|Voltage   I(typ)   I(min)   I(max)
-1.35V    -231.2mA   -242.8mA   -225.6mA
-1.186V   -124mA     -138.5mA   -116.4mA
-1.104V   -84.24mA   -96.52mA   -79.52mA
-981mV    -54.97mA   -56.84mA   -57.27mA
-858mV    -42.28mA   -40.3mA    -44.26mA
-489mV    -16.26mA   -15.88mA   -14.89mA
2.217V    75.77mA    74.45mA    74.87mA
2.34V     86.09mA    101.7mA    83.46mA
2.422V    103.9mA    137.5mA    91.31mA
2.504V    140.3mA    184.6mA    110.3mA
2.586V    190.7mA    238.7mA    151.7mA
2.7V      271.8mA    320.2mA    229.8mA
[Pullup]
|Voltage   I(typ)   I(min)   I(max)
-1.35V    261.8mA    281.1mA    251mA
-1.195V   148.5mA    171.6mA    134.6mA
-1.072V   75.84mA    97.64mA    63.81mA
-990mV    47.24mA    61.35mA    42.95mA
-867mV    32.52mA    33.86mA    32.99mA
404mV     -12.56mA   -11.72mA   -11.74mA
1.921V    -50.89mA   -50.12mA   -47.34mA
2.208V    -69.32mA   -68.88mA   -66.82mA
2.331V    -80.1mA    -86.05mA   -78.31mA
2.454V    -102mA     -128.5mA   -91.83mA
2.577V    -158.7mA   -196.4mA   -129.2mA
2.7V      -238.6mA   -277.5mA   -204.4mA
[Ramp]
| variable   typ   min   max
dV/dt_r   0.492/0.165n   0.464/0.224n   0.493/0.132n
dV/dt_f   0.500/0.109n   0.476/0.146n   0.497/92.177p
R_load = 50.000
[Rising Waveform]
R_fixture= 50.000
V_fixture= 0.0
V_fixture_min= 0.0
V_fixture_max= 0.0
|time   V(typ)   V(min)   V(max)
0s        1.101uV    6.191uV    508.8nV
402ps     -395uV     69.01uV    10.52mV
457ps     -2.709mV   -85.22uV   117.1mV
530ps     16.74mV    -1.784mV   415mV
642ps     295.4mV    12.31mV    727.5mV
748ps     618.6mV    179.8mV    796.6mV
852ps     753.2mV    434.1mV    813mV
1.058ns   807.3mV    697.8mV    820.2mV
1.438ns   818.3mV    763.4mV    821.7mV
10ns      819.5mV    773.1mV    821.8mV
[Rising Waveform]
R_fixture= 50.000
V_fixture= 0.675
V_fixture_min= 0.656
V_fixture_max= 0.696
|time   V(typ)   V(min)   V(max)
0s        257.6mV    258.3mV    280.7mV
405ps     257.1mV    258.4mV    289.9mV
452ps     256.6mV    258.2mV    412.5mV
524ps     276.7mV    257.8mV    757.3mV
617ps     552.8mV    272.6mV    1.028V
706ps     889.4mV    429.6mV    1.085V
797ps     1.028V     697.5mV    1.1V
967ps     1.076V     973.2mV    1.106V
1.308ns   1.085V     1.036V     1.107V
10ns      1.087V     1.044V     1.107V
[Falling Waveform]
R_fixture= 50.000
V_fixture= 0.675
V_fixture_min= 0.656
V_fixture_max= 0.696
|time   V(typ)   V(min)   V(max)
0s        1.087V     1.044V     1.107V
391ps     1.087V     1.044V     1.105V
433ps     1.09V      1.044V     976.9mV
507ps     1.078V     1.047V     520.7mV
560ps     931.8mV    1.048V     363.8mV
626ps     555mV      1.004V     306.5mV
724ps     310.3mV    677.5mV    287.1mV
843ps     269mV      339.1mV    282.5mV
1.084ns   259.5mV    266.7mV    281mV
10ns      257.6mV    258.3mV    280.7mV
[Falling Waveform]
R_fixture= 50.000
V_fixture= 0.0
V_fixture_min= 0.0
V_fixture_max= 0.0
|time   V(typ)   V(min)   V(max)
0s        819.5mV    773.1mV    821.8mV
389ps     820.9mV    773.3mV    818.6mV
426ps     823mV      773.8mV    705.6mV
499ps     809.1mV    776.6mV    241.9mV
542ps     689.2mV    776.6mV    96.74mV
616ps     249.7mV    723.7mV    22.77mV
701ps     44.65mV    400.6mV    5.605mV
803ps     8.244mV    77.69mV    1.463mV
1.001ns   1.058mV    4.297mV    243.4uV
10ns      1.116uV    6.197uV    528.5nV
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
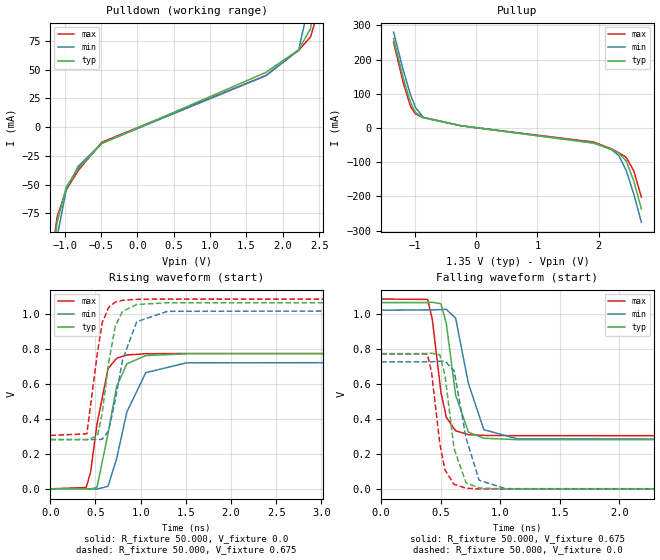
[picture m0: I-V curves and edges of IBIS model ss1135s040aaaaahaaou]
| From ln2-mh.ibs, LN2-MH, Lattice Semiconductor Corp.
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|   Model ss1135s040aaaaahaaou
[Model] ss1135s040aaaaahaaou
Model_type Output
Polarity   Non-Inverting
Enable   Active-High
Vmeas =  0.675V
Cref =  30.000pF
Rref =  50.000
Vref =  0.675V
C_comp   2.000pF   1.500pF   2.500pF
[Temperature Range]   25.000   0.125k   -40.000
[Voltage Range]   1.350V   1.310V   1.390V
[C Comp Corner]
C_comp   2.000pF   1.500pF   2.500pF
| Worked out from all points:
|   slope of the pulldown table from 0 to 0.203 V, typ, clamps not added: 35.6 ohm
|   slope of the pullup table from 0 to 0.203 V, typ, clamps not added: 36.9 ohm
|   rising waveform, R_fixture 50.000, V_fixture 0.0: 20-80 % time 161ps typ, 217ps min, 132ps max; typ from 0 V to 0.771 V
|   rising waveform, R_fixture 50.000, V_fixture 0.675: 20-80 % time 133ps typ, 179ps min, 110ps max; typ from 0.281 V to 1.06 V
|   falling waveform, R_fixture 50.000, V_fixture 0.675: 20-80 % time 97.9ps typ, 127ps min, 88.8ps max; typ from 1.06 V to 0.281 V
|   falling waveform, R_fixture 50.000, V_fixture 0.0: 20-80 % time 90.8ps typ, 114ps min, 86.5ps max; typ from 0.771 V to 0 V
[Pulldown]
|Voltage   I(typ)   I(min)   I(max)
-1.35V    -230.2mA   -241.8mA   -224.8mA
-1.186V   -122.6mA   -137.1mA   -115.1mA
-1.104V   -82.23mA   -94.83mA   -77.56mA
-981mV    -52.21mA   -54.48mA   -54.8mA
-817mV    -35.93mA   -34.15mA   -37.8mA
-489mV    -14.19mA   -13.95mA   -13.03mA
1.766V    47.58mA    44.68mA    44.9mA
2.217V    67.27mA    67.18mA    66.71mA
2.381V    85.59mA    113.1mA    78.51mA
2.504V    136mA      181.4mA    104.5mA
2.586V    187.6mA    236.1mA    148.1mA
2.7V      269.4mA    318mA      227.5mA
[Pullup]
|Voltage   I(typ)   I(min)   I(max)
-1.35V    261mA      280.3mA    250.4mA
-1.195V   147.5mA    170.6mA    133.7mA
-1.072V   74.22mA    96.24mA    62.19mA
-990mV    44.92mA    59.51mA    40.66mA
-867mV    29.85mA    31.46mA    30.62mA
-252mV    6.942mA    6.538mA    6.422mA
1.921V    -44.28mA   -43.92mA   -41.11mA
2.208V    -62.72mA   -62.77mA   -60.71mA
2.331V    -73.66mA   -80.81mA   -72.24mA
2.454V    -97.08mA   -124.9mA   -86.13mA
2.577V    -155.8mA   -193.9mA   -125.9mA
2.7V      -236.4mA   -275.4mA   -202.3mA
[Ramp]
| variable   typ   min   max
dV/dt_r   0.463/0.162n   0.435/0.218n   0.464/0.132n
dV/dt_f   0.472/0.111n   0.448/0.150n   0.469/94.402p
R_load = 50.000
[Rising Waveform]
R_fixture= 50.000
V_fixture= 0.0
V_fixture_min= 0.0
V_fixture_max= 0.0
|time   V(typ)   V(min)   V(max)
0s        1.224uV    6.848uV    563.4nV
397ps     -256.9uV   66.28uV    7.76mV
446ps     -1.758mV   22.75uV    94.04mV
518ps     10.26mV    -1.18mV    374.1mV
639ps     316.1mV    14.81mV    684.8mV
734ps     583.4mV    172.2mV    745mV
848ps     713.6mV    439.3mV    764mV
1.057ns   760.6mV    663mV      771mV
1.508ns   770.5mV    719.1mV    772.4mV
10ns      771.2mV    725.1mV    772.5mV
[Rising Waveform]
R_fixture= 50.000
V_fixture= 0.675
V_fixture_min= 0.656
V_fixture_max= 0.696
|time   V(typ)   V(min)   V(max)
0s        280.9mV    281.2mV    304.7mV
405ps     280.4mV    281.3mV    314.3mV
522ps     301.2mV    280.8mV    777.6mV
575ps     433.8mV    283.3mV    947.7mV
646ps     721.7mV    331.1mV    1.036V
720ps     927.9mV    509.2mV    1.066V
800ps     1.013V     736.1mV    1.076V
957ps     1.052V     954mV      1.082V
1.297ns   1.062V     1.013V     1.083V
10ns      1.063V     1.021V     1.083V
[Falling Waveform]
R_fixture= 50.000
V_fixture= 0.675
V_fixture_min= 0.656
V_fixture_max= 0.696
|time   V(typ)   V(min)   V(max)
0s        1.063V     1.02V      1.083V
390ps     1.063V     1.021V     1.081V
429ps     1.065V     1.021V     968.5mV
502ps     1.056V     1.023V     550.7mV
547ps     944.3mV    1.024V     409.6mV
625ps     536.1mV    974.7mV    332.5mV
733ps     324.7mV    600.9mV    310.8mV
862ps     290mV      339.1mV    306.2mV
1.145ns   282mV      286.6mV    304.9mV
10ns      280.9mV    281.2mV    304.7mV
[Falling Waveform]
R_fixture= 50.000
V_fixture= 0.0
V_fixture_min= 0.0
V_fixture_max= 0.0
|time   V(typ)   V(min)   V(max)
0s        771.2mV    725.1mV    772.5mV
388ps     772.6mV    725.3mV    769.2mV
423ps     774.6mV    725.9mV    666mV
492ps     765.4mV    728.6mV    260.6mV
536ps     649.7mV    728.7mV    109mV
612ps     231.4mV    676mV      27.12mV
713ps     35.67mV    290.3mV    5.469mV
823ps     6.748mV    50.57mV    1.315mV
1.043ns   761.3uV    2.985mV    173.8uV
10ns      1.24uV     6.857uV    583.2nV
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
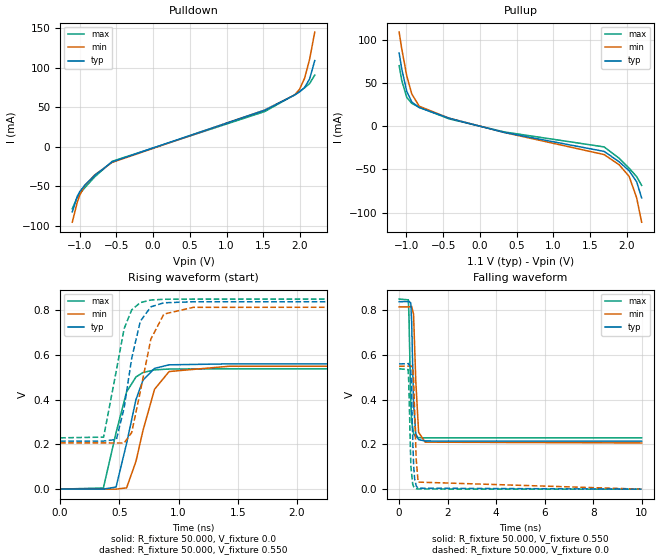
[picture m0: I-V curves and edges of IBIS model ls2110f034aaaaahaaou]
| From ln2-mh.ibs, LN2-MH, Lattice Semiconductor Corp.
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|   Model ls2110f034aaaaahaaou
[Model] ls2110f034aaaaahaaou
Model_type Output
Polarity   Non-Inverting
Enable   Active-High
Vmeas =  0.550V
Cref =  20.000pF
Rref =  50.000
Vref =  0.600V
C_comp   2.000pF   1.500pF   2.500pF
[Temperature Range]   25.000   0.125k   -40.000
[Voltage Range]   1.100V   1.070V   1.130V
[C Comp Corner]
C_comp   2.000pF   1.500pF   2.500pF
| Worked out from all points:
|   slope of the pulldown table from 0 to 0.165 V, typ, clamps not added: 31.9 ohm
|   slope of the pullup table from 0 to 0.165 V, typ, clamps not added: 45.3 ohm
|   rising waveform, R_fixture 50.000, V_fixture 0.0: 20-80 % time 140ps typ, 159ps min, 139ps max; typ from 0 V to 0.56 V
|   rising waveform, R_fixture 50.000, V_fixture 0.550: 20-80 % time 121ps typ, 138ps min, 118ps max; typ from 0.214 V to 0.837 V
|   falling waveform, R_fixture 50.000, V_fixture 0.550: 20-80 % time 86.9ps typ, 110ps min, 77.1ps max; typ from 0.837 V to 0.214 V
|   falling waveform, R_fixture 50.000, V_fixture 0.0: 20-80 % time 82.8ps typ, 100ps min, 75.1ps max; typ from 0.56 V to 0 V
[Pulldown]
|Voltage   I(typ)   I(min)   I(max)
-1.1V     -82.08mA   -95.12mA   -78.17mA
-1.032V   -62.45mA   -69.98mA   -63.64mA
-998mV    -56.5mA    -61mA      -59.15mA
-930mV    -48.3mA    -48.87mA   -51.6mA
-794mV    -35.85mA   -35.33mA   -37.78mA
-556mV    -18.82mA   -19.52mA   -18.2mA
1.518V    46.44mA    46.55mA    44.66mA
1.926V    65.51mA    65.6mA     65.84mA
1.994V    69.6mA     72.99mA    70.2mA
2.062V    75.1mA     86.91mA    74.73mA
2.13V     85.87mA    110.7mA    80.09mA
2.2V      109.1mA    145.1mA    90.74mA
[Pullup]
|Voltage   I(typ)   I(min)   I(max)
-1.1V     84.75mA    109.1mA    70.17mA
-1.064V   66.08mA    89.38mA    52.9mA
-996mV    40.39mA    58.24mA    33.32mA
-928mV    28.1mA     37.38mA    26.55mA
-826mV    21.65mA    23.15mA    21.93mA
-418mV    9.287mA    9.351mA    8.54mA
330mV     -7.158mA   -7.159mA   -6.543mA
1.69V     -29.12mA   -32.79mA   -23.92mA
1.894V    -41.11mA   -44.56mA   -37.08mA
2.03V     -51.55mA   -58.07mA   -48.59mA
2.132V    -64.19mA   -82.78mA   -58.31mA
2.2V      -82.98mA   -111.1mA   -68.47mA
[Ramp]
| variable   typ   min   max
dV/dt_r   0.336/0.140n   0.330/0.159n   0.323/0.139n
dV/dt_f   0.402/94.712p   0.393/0.123n   0.404/81.402p
R_load = 50.000
[Rising Waveform]
R_fixture= 50.000
V_fixture= 0.0
V_fixture_min= 0.0
V_fixture_max= 0.0
|time   V(typ)   V(min)   V(max)
0s        969.9nV    5.215uV    445nV
365ps     68.76uV    39.77uV    4.88mV
472ps     9.099mV    -310.9uV   251.8mV
561ps     204.2mV    5.568mV    434.3mV
640ps     400mV      123.7mV    501mV
699ps     486.2mV    261.2mV    520.7mV
797ps     539.4mV    446.1mV    532.8mV
920ps     555.3mV    525.3mV    536.5mV
1.428ns   559.5mV    549mV      537.5mV
10ns      559.5mV    549.2mV    537.6mV
[Rising Waveform]
R_fixture= 50.000
V_fixture= 0.550
V_fixture_min= 0.534
V_fixture_max= 0.568
|time   V(typ)   V(min)   V(max)
0s        214.4mV    206.4mV    229.1mV
367ps     214.5mV    206.4mV    232.1mV
475ps     222.1mV    206mV      531.1mV
540ps     362.3mV    205.7mV    716.6mV
604ps     584.6mV    252.7mV    800.9mV
677ps     750mV      436.3mV    833.3mV
766ps     814.4mV    670.4mV    844.8mV
876ps     832.5mV    782mV      848.1mV
1.126ns   837.1mV    812.2mV    849mV
10ns      837.4mV    813.9mV    849.1mV
[Falling Waveform]
R_fixture= 50.000
V_fixture= 0.550
V_fixture_min= 0.534
V_fixture_max= 0.568
|time   V(typ)   V(min)   V(max)
0s        837.4mV    813.9mV    849.1mV
378ps     837.9mV    813.9mV    845.6mV
404ps     839mV      814.1mV    776.3mV
479ps     831.7mV    815.7mV    386.8mV
515ps     749.9mV    817.1mV    305.8mV
594ps     384.6mV    781.7mV    247.6mV
686ps     247.6mV    483.5mV    233.8mV
802ps     221.3mV    254.1mV    230.3mV
1.072ns   215.1mV    210mV      229.2mV
10ns      214.4mV    206.4mV    229.1mV
[Falling Waveform]
R_fixture= 50.000
V_fixture= 0.0
V_fixture_min= 0.0
V_fixture_max= 0.0
|time   V(typ)   V(min)   V(max)
0s        559.5mV    549.2mV    537.5mV
373ps     560.5mV    549.3mV    534.1mV
395ps     561.5mV    549.5mV    481.4mV
483ps     537.2mV    552.3mV    103.5mV
558ps     228.7mV    542.7mV    22.98mV
598ps     104.5mV    484mV      11.19mV
638ps     46.77mV    351.1mV    5.765mV
702ps     14.7mV     135mV      2.231mV
782ps     4.394mV    31.53mV    822.8uV
10ns      978.5nV    5.217uV    457nV
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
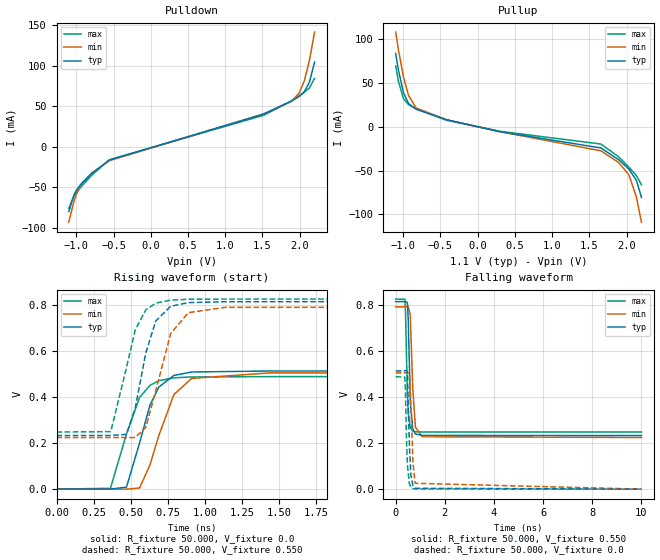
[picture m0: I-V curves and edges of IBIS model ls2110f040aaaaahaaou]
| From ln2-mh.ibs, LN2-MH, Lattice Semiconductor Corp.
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|   Model ls2110f040aaaaahaaou
[Model] ls2110f040aaaaahaaou
Model_type Output
Polarity   Non-Inverting
Enable   Active-High
Vmeas =  0.550V
Cref =  20.000pF
Rref =  50.000
Vref =  0.600V
C_comp   2.000pF   1.500pF   2.500pF
[Temperature Range]   25.000   0.125k   -40.000
[Voltage Range]   1.100V   1.070V   1.130V
[C Comp Corner]
C_comp   2.000pF   1.500pF   2.500pF
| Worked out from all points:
|   slope of the pulldown table from 0 to 0.165 V, typ, clamps not added: 36.9 ohm
|   slope of the pullup table from 0 to 0.165 V, typ, clamps not added: 52.6 ohm
|   rising waveform, R_fixture 50.000, V_fixture 0.0: 20-80 % time 138ps typ, 157ps min, 139ps max; typ from 0 V to 0.515 V
|   rising waveform, R_fixture 50.000, V_fixture 0.550: 20-80 % time 117ps typ, 134ps min, 117ps max; typ from 0.233 V to 0.816 V
|   falling waveform, R_fixture 50.000, V_fixture 0.550: 20-80 % time 88.7ps typ, 112ps min, 79.8ps max; typ from 0.816 V to 0.233 V
|   falling waveform, R_fixture 50.000, V_fixture 0.0: 20-80 % time 83.1ps typ, 102ps min, 77.4ps max; typ from 0.515 V to 0 V
[Pulldown]
|Voltage   I(typ)   I(min)   I(max)
-1.1V     -80.13mA   -93.34mA   -76.18mA
-1.032V   -59.99mA   -67.81mA   -61.23mA
-998mV    -53.9mA    -58.64mA   -56.69mA
-930mV    -45.61mA   -46.27mA   -49.16mA
-794mV    -33.29mA   -32.75mA   -35.47mA
-556mV    -16.64mA   -17.34mA   -16.19mA
1.518V    40.3mA     40.42mA    38.8mA
1.892V    56.34mA    56.06mA    56.7mA
1.994V    62.1mA     66.32mA    62.84mA
2.062V    67.75mA    81.17mA    67.18mA
2.13V     79.49mA    106.1mA    72.58mA
2.2V      104.4mA    141.5mA    84.35mA
[Pullup]
|Voltage   I(typ)   I(min)   I(max)
-1.1V     84mA       108.3mA    69.59mA
-1.064V   65.2mA     88.5mA     52.17mA
-996mV    39.18mA    57.12mA    32.26mA
-928mV    26.62mA    35.99mA    25.36mA
-826mV    20.08mA    21.54mA    20.71mA
-418mV    8.066mA    8.138mA    7.463mA
296mV     -5.553mA   -5.54mA    -5.094mA
1.656V    -24.22mA   -27.49mA   -19.73mA
1.894V    -37.66mA   -40.83mA   -34.34mA
2.03V     -48.25mA   -54.74mA   -45.99mA
2.132V    -61.34mA   -80.24mA   -55.88mA
2.2V      -80.8mA    -109.1mA   -66.39mA
[Ramp]
| variable   typ   min   max
dV/dt_r   0.309/0.138n   0.304/0.157n   0.294/0.139n
dV/dt_f   0.379/96.902p   0.371/0.127n   0.381/83.827p
R_load = 50.000
[Rising Waveform]
R_fixture= 50.000
V_fixture= 0.0
V_fixture_min= 0.0
V_fixture_max= 0.0
|time   V(typ)   V(min)   V(max)
0s        1.078uV    5.78uV     493nV
363ps     71.7uV     44.41uV    3.423mV
471ps     8.702mV    -273.5uV   240.1mV
559ps     201mV      4.881mV    399.4mV
629ps     365.8mV    105.2mV    452.1mV
689ps     444.7mV    233.8mV    472mV
790ps     495.2mV    411.7mV    484.7mV
910ps     510.1mV    482.3mV    488.7mV
1.44ns    514.5mV    506.3mV    489.9mV
10ns      514.6mV    506.5mV    490mV
[Rising Waveform]
R_fixture= 50.000
V_fixture= 0.550
V_fixture_min= 0.534
V_fixture_max= 0.568
|time   V(typ)   V(min)   V(max)
0s        233.5mV    224.9mV    248.7mV
365ps     233.6mV    225mV      250.3mV
471ps     238.3mV    224.6mV    529.3mV
530ps     352.7mV    224.4mV    693.8mV
601ps     593.6mV    268.8mV    780.7mV
668ps     731.9mV    428.1mV    809.9mV
768ps     796.1mV    677.5mV    823.3mV
888ps     812.4mV    768.6mV    826.9mV
1.137ns   816.2mV    791.9mV    827.7mV
10ns      816.5mV    793.4mV    827.8mV
[Falling Waveform]
R_fixture= 50.000
V_fixture= 0.550
V_fixture_min= 0.534
V_fixture_max= 0.568
|time   V(typ)   V(min)   V(max)
0s        816.4mV    793.4mV    827.8mV
374ps     816.9mV    793.4mV    826.9mV
401ps     817.9mV    793.6mV    765.7mV
476ps     811.9mV    795.1mV    404.8mV
510ps     739.3mV    796.4mV    331.1mV
594ps     383.7mV    756.3mV    268.4mV
692ps     263.5mV    442.3mV    253.3mV
802ps     240.4mV    270.2mV    249.9mV
1.073ns   234.1mV    228.3mV    248.8mV
10ns      233.5mV    224.9mV    248.7mV
[Falling Waveform]
R_fixture= 50.000
V_fixture= 0.0
V_fixture_min= 0.0
V_fixture_max= 0.0
|time   V(typ)   V(min)   V(max)
0s        514.6mV    506.5mV    489.9mV
371ps     515.5mV    506.6mV    487.5mV
392ps     516.4mV    506.8mV    442.2mV
444ps     517.9mV    507.9mV    201.7mV
479ps     496.4mV    509.4mV    102.5mV
558ps     191.3mV    499.1mV    23.6mV
616ps     64.27mV    378.9mV    8.954mV
703ps     14.61mV    113.1mV    2.446mV
792ps     4.07mV     25.54mV    790.1uV
10ns      1.088uV    5.784uV    506nV
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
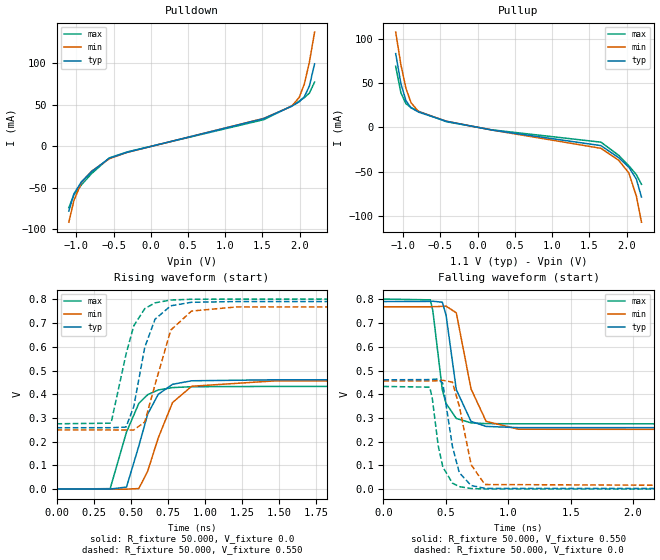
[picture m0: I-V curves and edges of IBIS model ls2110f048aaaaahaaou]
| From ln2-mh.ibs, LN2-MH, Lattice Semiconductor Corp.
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|   Model ls2110f048aaaaahaaou
[Model] ls2110f048aaaaahaaou
Model_type Output
Polarity   Non-Inverting
Enable   Active-High
Vmeas =  0.550V
Cref =  20.000pF
Rref =  50.000
Vref =  0.600V
C_comp   2.000pF   1.500pF   2.500pF
[Temperature Range]   25.000   0.125k   -40.000
[Voltage Range]   1.100V   1.070V   1.130V
[C Comp Corner]
C_comp   2.000pF   1.500pF   2.500pF
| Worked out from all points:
|   slope of the pulldown table from 0 to 0.165 V, typ, clamps not added: 44.4 ohm
|   slope of the pullup table from 0 to 0.165 V, typ, clamps not added: 63.1 ohm
|   rising waveform, R_fixture 50.000, V_fixture 0.0: 20-80 % time 134ps typ, 159ps min, 130ps max; typ from 0 V to 0.461 V
|   rising waveform, R_fixture 50.000, V_fixture 0.550: 20-80 % time 111ps typ, 133ps min, 106ps max; typ from 0.259 V to 0.791 V
|   falling waveform, R_fixture 50.000, V_fixture 0.550: 20-80 % time 94.3ps typ, 122ps min, 81.9ps max; typ from 0.791 V to 0.259 V
|   falling waveform, R_fixture 50.000, V_fixture 0.0: 20-80 % time 87.7ps typ, 108ps min, 80.1ps max; typ from 0.461 V to 0 V
[Pulldown]
|Voltage   I(typ)   I(min)   I(max)
-1.1V     -78.02mA   -91.42mA   -73.95mA
-1.032V   -57.31mA   -65.45mA   -58.5mA
-930mV    -42.66mA   -43.45mA   -46.38mA
-794mV    -30.47mA   -29.92mA   -32.83mA
-556mV    -14.23mA   -14.95mA   -13.9mA
-318mV    -7.17mA    -7.312mA   -6.76mA
1.518V    33.49mA    33.69mA    32.15mA
1.892V    48.25mA    48.32mA    48.74mA
1.994V    53.77mA    59.12mA    54.52mA
2.062V    59.67mA    75.04mA    58.65mA
2.13V     72.64mA    101.3mA    64.17mA
2.2V      99.43mA    137.7mA    77.46mA
[Pullup]
|Voltage   I(typ)   I(min)   I(max)
-1.1V     83.26mA    107.6mA    68.98mA
-1.03V    49.39mA    70.69mA    39.04mA
-962mV    30.1mA     43.95mA    26.72mA
-894mV    22.07mA    27.83mA    22.34mA
-792mV    17.23mA    17.69mA    18.14mA
-418mV    6.832mA    6.929mA    6.352mA
194mV     -3.07mA    -3.061mA   -2.816mA
1.656V    -20.62mA   -23.68mA   -16.72mA
1.894V    -34.2mA    -37.13mA   -31.55mA
2.03V     -44.96mA   -51.44mA   -43.37mA
2.132V    -58.52mA   -77.74mA   -53.44mA
2.2V      -78.64mA   -107.1mA   -64.31mA
[Ramp]
| variable   typ   min   max
dV/dt_r   0.277/0.134n   0.274/0.159n   0.260/0.130n
dV/dt_f   0.349/0.104n   0.341/0.139n   0.349/85.568p
R_load = 50.000
[Rising Waveform]
R_fixture= 50.000
V_fixture= 0.0
V_fixture_min= 0.0
V_fixture_max= 0.0
|time   V(typ)   V(min)   V(max)
0s        1.218uV    6.515uV    556.9nV
361ps     78.91uV    51.81uV    1.992mV
471ps     8.753mV    -264.8uV   240.5mV
554ps     181.8mV    2.355mV    361.6mV
614ps     316.9mV    76.27mV    398.4mV
685ps     400mV      216.3mV    418.2mV
781ps     442.1mV    365.1mV    428.2mV
910ps     456.9mV    433.8mV    431.9mV
1.458ns   461mV      456.1mV    433.1mV
10ns      461.1mV    456.3mV    433.1mV
[Rising Waveform]
R_fixture= 50.000
V_fixture= 0.550
V_fixture_min= 0.534
V_fixture_max= 0.568
|time   V(typ)   V(min)   V(max)
0s        258.9mV    249.5mV    275.5mV
367ps     259mV      249.5mV    278.1mV
468ps     261.6mV    249.2mV    569.4mV
520ps     347.9mV    249.1mV    688.5mV
594ps     598.2mV    283.8mV    761.2mV
663ps     716.4mV    439.7mV    785.7mV
769ps     773.2mV    670.8mV    797.5mV
909ps     788.1mV    751mV      800.8mV
1.209ns   791.1mV    768.3mV    801.5mV
10ns      791.3mV    769.2mV    801.6mV
[Falling Waveform]
R_fixture= 50.000
V_fixture= 0.550
V_fixture_min= 0.534
V_fixture_max= 0.568
|time   V(typ)   V(min)   V(max)
0s        791.2mV    769.2mV    801.6mV
376ps     791.7mV    769.2mV    798.3mV
396ps     792.4mV    769.3mV    752.6mV
472ps     788.4mV    770.7mV    419.1mV
502ps     734.2mV    771.9mV    361.5mV
584ps     419.8mV    743.5mV    298.3mV
702ps     285.8mV    422.8mV    279.6mV
823ps     264.6mV    285.9mV    276.4mV
1.083ns   259.4mV    252.7mV    275.6mV
10ns      258.9mV    249.5mV    275.5mV
[Falling Waveform]
R_fixture= 50.000
V_fixture= 0.0
V_fixture_min= 0.0
V_fixture_max= 0.0
|time   V(typ)   V(min)   V(max)
0s        461.1mV    456.3mV    433.1mV
371ps     462mV      456.3mV    430.2mV
391ps     462.8mV    456.5mV    385.4mV
439ps     464.5mV    457.5mV    183.3mV
476ps     446mV      459mV      93.64mV
553ps     180.1mV    451.2mV    25.4mV
608ps     69.42mV    350.2mV    10.68mV
703ps     15.54mV    103.3mV    2.715mV
813ps     3.489mV    19.57mV    673.8uV
10ns      1.229uV    6.522uV    570.5nV
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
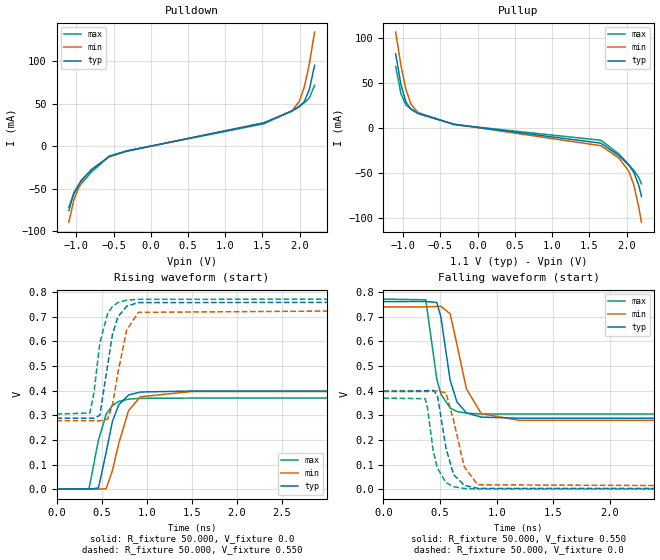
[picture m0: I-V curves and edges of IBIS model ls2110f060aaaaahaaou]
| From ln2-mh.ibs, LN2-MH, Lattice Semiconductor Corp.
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|   Model ls2110f060aaaaahaaou
[Model] ls2110f060aaaaahaaou
Model_type Output
Polarity   Non-Inverting
Enable   Active-High
Vmeas =  0.550V
Cref =  20.000pF
Rref =  50.000
Vref =  0.600V
C_comp   2.000pF   1.500pF   2.500pF
[Temperature Range]   25.000   0.125k   -40.000
[Voltage Range]   1.100V   1.070V   1.130V
[C Comp Corner]
C_comp   2.000pF   1.500pF   2.500pF
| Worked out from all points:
|   slope of the pulldown table from 0 to 0.165 V, typ, clamps not added: 54.8 ohm
|   slope of the pullup table from 0 to 0.165 V, typ, clamps not added: 78.5 ohm
|   rising waveform, R_fixture 50.000, V_fixture 0.0: 20-80 % time 145ps typ, 174ps min, 136ps max; typ from 0 V to 0.398 V
|   rising waveform, R_fixture 50.000, V_fixture 0.550: 20-80 % time 119ps typ, 142ps min, 113ps max; typ from 0.288 V to 0.762 V
|   falling waveform, R_fixture 50.000, V_fixture 0.550: 20-80 % time 106ps typ, 137ps min, 90.5ps max; typ from 0.762 V to 0.288 V
|   falling waveform, R_fixture 50.000, V_fixture 0.0: 20-80 % time 96.8ps typ, 120ps min, 87.1ps max; typ from 0.398 V to 0 V
[Pulldown]
|Voltage   I(typ)   I(min)   I(max)
-1.1V     -76.12mA   -89.68mA   -72.01mA
-1.032V   -54.89mA   -63.31mA   -56.1mA
-930mV    -39.97mA   -40.86mA   -43.93mA
-794mV    -27.89mA   -27.32mA   -30.51mA
-556mV    -12.02mA   -12.75mA   -11.86mA
-318mV    -5.813mA   -5.931mA   -5.496mA
1.518V    27.25mA    27.47mA    26.2mA
1.892V    40.87mA    41.2mA     41.62mA
1.994V    46.21mA    52.59mA    47.06mA
2.062V    52.43mA    69.57mA    51.01mA
2.13V     66.65mA    96.98mA    56.74mA
2.2V      95.12mA    134.3mA    71.6mA
[Pullup]
|Voltage   I(typ)   I(min)   I(max)
-1.1V     82.53mA    106.8mA    68.41mA
-1.03V    48.37mA    69.71mA    38.15mA
-962mV    28.74mA    42.68mA    25.58mA
-894mV    20.54mA    26.34mA    21.13mA
-792mV    15.67mA    16.06mA    16.92mA
-316mV    4.023mA    4.079mA    3.66mA
1.656V    -17.04mA   -19.86mA   -13.78mA
1.894V    -30.75mA   -33.42mA   -28.82mA
2.03V     -41.68mA   -48.15mA   -40.79mA
2.098V    -49.58mA   -63.85mA   -47.32mA
2.166V    -64.54mA   -89.12mA   -55.66mA
2.2V      -76.53mA   -105.1mA   -62.28mA
[Ramp]
| variable   typ   min   max
dV/dt_r   0.239/0.145n   0.238/0.174n   0.222/0.137n
dV/dt_f   0.314/0.117n   0.307/0.157n   0.314/95.034p
R_load = 50.000
[Rising Waveform]
R_fixture= 50.000
V_fixture= 0.0
V_fixture_min= 0.0
V_fixture_max= 0.0
|time   V(typ)   V(min)   V(max)
0s        1.381uV    7.371uV    628.7nV
360ps     80.02uV    61.25uV    1.647mV
465ps     4.503mV    -162uV     199.4mV
550ps     149.6mV    1.571mV    304.1mV
618ps     273.5mV    73.8mV     339.2mV
690ps     342.5mV    185.9mV    356mV
798ps     381.9mV    318.5mV    365.5mV
928ps     394.4mV    375.1mV    368.7mV
1.498ns   398.4mV    396.3mV    369.8mV
10ns      398.5mV    396.5mV    369.8mV
[Rising Waveform]
R_fixture= 50.000
V_fixture= 0.550
V_fixture_min= 0.534
V_fixture_max= 0.568
|time   V(typ)   V(min)   V(max)
0s        287.8mV    277.7mV    304.9mV
369ps     287.9mV    277.7mV    308.9mV
415ps     287.5mV    277.7mV    392.8mV
480ps     299.9mV    277.3mV    593.7mV
566ps     502.3mV    284.2mV    712.7mV
620ps     628.7mV    340.7mV    742mV
680ps     699.2mV    471.9mV    757.6mV
777ps     742.7mV    645.3mV    767.4mV
907ps     757.4mV    717.9mV    770.8mV
10ns      761.5mV    740.2mV    771.8mV
[Falling Waveform]
R_fixture= 50.000
V_fixture= 0.550
V_fixture_min= 0.534
V_fixture_max= 0.568
|time   V(typ)   V(min)   V(max)
0s        761.5mV    740.2mV    771.8mV
374ps     762mV      740.2mV    768.8mV
471ps     758.1mV    741.5mV    447.6mV
507ps     700mV      742.5mV    386.5mV
589ps     442.1mV    712.2mV    329.3mV
649ps     354.2mV    587.3mV    315.5mV
733ps     309.7mV    406.9mV    308.4mV
863ps     292.6mV    307.1mV    305.6mV
1.193ns   288.1mV    279.6mV    304.9mV
10ns      287.8mV    277.6mV    304.9mV
[Falling Waveform]
R_fixture= 50.000
V_fixture= 0.0
V_fixture_min= 0.0
V_fixture_max= 0.0
|time   V(typ)   V(min)   V(max)
0s        398.5mV    396.5mV    369.8mV
369ps     399.3mV    396.5mV    367.3mV
388ps     400.1mV    396.6mV    332.2mV
440ps     401mV      397.6mV    154.9mV
476ps     382.5mV    398.9mV    86.16mV
552ps     167.6mV    391.1mV    26.8mV
619ps     59.54mV    280.2mV    10.17mV
713ps     15.57mV    91.5mV     2.855mV
833ps     3.393mV    17.79mV    663.5uV
10ns      1.394uV    7.383uV    643.4nV
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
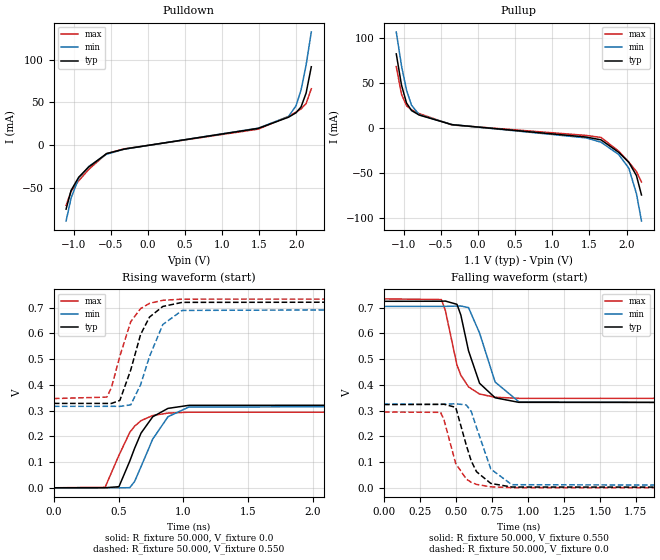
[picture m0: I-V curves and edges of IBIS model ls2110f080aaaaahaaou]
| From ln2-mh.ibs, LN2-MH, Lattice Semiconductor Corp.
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|   Model ls2110f080aaaaahaaou
[Model] ls2110f080aaaaahaaou
Model_type Output
Polarity   Non-Inverting
Enable   Active-High
Vmeas =  0.550V
Cref =  20.000pF
Rref =  50.000
Vref =  0.600V
C_comp   2.000pF   1.500pF   2.500pF
[Temperature Range]   25.000   0.125k   -40.000
[Voltage Range]   1.100V   1.070V   1.130V
[C Comp Corner]
C_comp   2.000pF   1.500pF   2.500pF
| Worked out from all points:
|   slope of the pulldown table from 0 to 0.165 V, typ, clamps not added: 73.8 ohm
|   slope of the pullup table from 0 to 0.165 V, typ, clamps not added: 104 ohm
|   rising waveform, R_fixture 50.000, V_fixture 0.0: 20-80 % time 173ps typ, 190ps min, 166ps max; typ from 0 V to 0.324 V
|   rising waveform, R_fixture 50.000, V_fixture 0.550: 20-80 % time 151ps typ, 166ps min, 141ps max; typ from 0.328 V to 0.725 V
|   falling waveform, R_fixture 50.000, V_fixture 0.550: 20-80 % time 118ps typ, 139ps min, 108ps max; typ from 0.725 V to 0.328 V
|   falling waveform, R_fixture 50.000, V_fixture 0.0: 20-80 % time 110ps typ, 122ps min, 102ps max; typ from 0.324 V to 0 V
[Pulldown]
|Voltage   I(typ)   I(min)   I(max)
-1.1V     -74.32mA   -88.15mA   -70.01mA
-1.032V   -52.39mA   -61.23mA   -53.47mA
-930mV    -37.09mA   -38.15mA   -41.2mA
-794mV    -25.11mA   -24.54mA   -27.91mA
-556mV    -9.618mA   -10.36mA   -9.575mA
-318mV    -4.323mA   -4.427mA   -4.063mA
1.484V    19.76mA    20.03mA    18.88mA
1.892V    32.77mA    33.6mA     33.64mA
1.994V    37.99mA    46.04mA    38.71mA
2.062V    44.81mA    64.59mA    42.51mA
2.13V     60.93mA    93.6mA     48.72mA
2.2V      91.63mA    132.1mA    65.98mA
[Pullup]
|Voltage   I(typ)   I(min)   I(max)
-1.1V     82.02mA    106.3mA    67.94mA
-1.03V    47.49mA    68.99mA    37.3mA
-962mV    27.45mA    41.64mA    24.41mA
-894mV    19.03mA    24.95mA    19.89mA
-792mV    14.11mA    14.46mA    15.68mA
-350mV    3.417mA    3.527mA    3.119mA
1.452V    -10.29mA   -11.24mA   -8.503mA
1.656V    -13.46mA   -16.07mA   -10.79mA
1.894V    -27.35mA   -29.79mA   -26.08mA
2.03V     -38.47mA   -45.05mA   -38.22mA
2.132V    -53.12mA   -73.16mA   -48.65mA
2.2V      -74.7mA    -103.6mA   -60.32mA
[Ramp]
| variable   typ   min   max
dV/dt_r   0.194/0.174n   0.195/0.190n   0.177/0.166n
dV/dt_f   0.266/0.131n   0.261/0.160n   0.264/0.117n
R_load = 50.000
[Rising Waveform]
R_fixture= 50.000
V_fixture= 0.0
V_fixture_min= 0.0
V_fixture_max= 0.0
|time   V(typ)   V(min)   V(max)
0s        1.604uV    8.538uV    728.8nV
396ps     166.9uV    120.8uV    1.694mV
503ps     4.126mV    -297.8uV   126.2mV
587ps     104mV      406.2uV    215.4mV
624ps     153.2mV    24.56mV    239.3mV
674ps     212.7mV    82.4mV     261mV
764ps     276mV      189.2mV    281mV
882ps     308.6mV    276.1mV    290.4mV
1.042ns   320.4mV    313.6mV    293.8mV
10ns      323.6mV    325mV      294.6mV
[Rising Waveform]
R_fixture= 50.000
V_fixture= 0.550
V_fixture_min= 0.534
V_fixture_max= 0.568
|time   V(typ)   V(min)   V(max)
0s        328mV      316.5mV    346.8mV
410ps     327.9mV    316.6mV    352.5mV
445ps     327.8mV    316.7mV    389.4mV
510ps     339.5mV    316.4mV    511.4mV
594ps     457.7mV    322.2mV    645.4mV
670ps     595.4mV    400mV      696.5mV
739ps     663.5mV    510.2mV    716.9mV
842ps     704.9mV    634.6mV    728.8mV
992ps     720.8mV    689.5mV    733.3mV
10ns      724.9mV    705.1mV    734.4mV
[Falling Waveform]
R_fixture= 50.000
V_fixture= 0.550
V_fixture_min= 0.534
V_fixture_max= 0.568
|time   V(typ)   V(min)   V(max)
0s        724.9mV    705.1mV    734.4mV
399ps     725.2mV    705.1mV    731.7mV
426ps     725.9mV    705.2mV    689.5mV
507ps     713.2mV    706.4mV    476.7mV
534ps     671.1mV    706.7mV    437.5mV
587ps     532.9mV    700.6mV    392.4mV
664ps     406.3mV    601.4mV    364.5mV
772ps     350mV      411.1mV    352.1mV
937ps     332.3mV    334.4mV    347.9mV
10ns      328mV      316.5mV    346.8mV
[Falling Waveform]
R_fixture= 50.000
V_fixture= 0.0
V_fixture_min= 0.0
V_fixture_max= 0.0
|time   V(typ)   V(min)   V(max)
0s        323.6mV    325mV      294.6mV
393ps     324.2mV    325mV      293.5mV
416ps     324.8mV    325.1mV    265.8mV
498ps     313mV      326.7mV    94.82mV
572ps     165.1mV    322mV      33.82mV
606ps     104.4mV    296.7mV    21.56mV
643ps     62.55mV    233.8mV    13.33mV
742ps     17.14mV    73.09mV    3.958mV
888ps     3.16mV     12.22mV    831.9uV
10ns      1.614uV    8.545uV    744nV
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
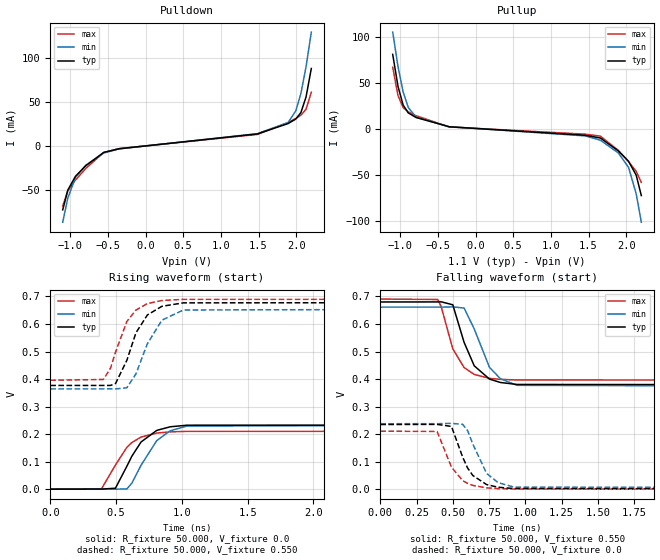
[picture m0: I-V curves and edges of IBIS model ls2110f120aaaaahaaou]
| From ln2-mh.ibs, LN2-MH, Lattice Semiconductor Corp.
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|   Model ls2110f120aaaaahaaou
[Model] ls2110f120aaaaahaaou
Model_type Output
Polarity   Non-Inverting
Enable   Active-High
Vmeas =  0.550V
Cref =  20.000pF
Rref =  50.000
Vref =  0.600V
C_comp   2.000pF   1.500pF   2.500pF
[Temperature Range]   25.000   0.125k   -40.000
[Voltage Range]   1.100V   1.070V   1.130V
[C Comp Corner]
C_comp   2.000pF   1.500pF   2.500pF
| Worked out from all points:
|   slope of the pulldown table from 0 to 0.165 V, typ, clamps not added: 108 ohm
|   slope of the pullup table from 0 to 0.165 V, typ, clamps not added: 156 ohm
|   rising waveform, R_fixture 50.000, V_fixture 0.0: 20-80 % time 177ps typ, 191ps min, 172ps max; typ from 0 V to 0.235 V
|   rising waveform, R_fixture 50.000, V_fixture 0.550: 20-80 % time 154ps typ, 169ps min, 143ps max; typ from 0.377 V to 0.68 V
|   falling waveform, R_fixture 50.000, V_fixture 0.550: 20-80 % time 129ps typ, 145ps min, 121ps max; typ from 0.68 V to 0.377 V
|   falling waveform, R_fixture 50.000, V_fixture 0.0: 20-80 % time 120ps typ, 130ps min, 115ps max; typ from 0.235 V to 0 V
[Pulldown]
|Voltage   I(typ)   I(min)   I(max)
-1.1V     -72.47mA   -86.44mA   -68.13mA
-1.032V   -50.01mA   -59.13mA   -51.09mA
-930mV    -34.39mA   -35.58mA   -38.74mA
-794mV    -22.52mA   -21.93mA   -25.57mA
-556mV    -7.388mA   -8.135mA   -7.523mA
-352mV    -3.262mA   -3.386mA   -3.076mA
1.484V    13.54mA    13.83mA    12.96mA
1.892V    25.3mA     26.48mA    26.4mA
1.994V    30.4mA     39.74mA    31.14mA
2.062V    37.79mA    59.46mA    34.81mA
2.13V     55.42mA    89.57mA    41.52mA
2.2V      87.69mA    128.9mA    60.76mA
[Pullup]
|Voltage   I(typ)   I(min)   I(max)
-1.1V     81.3mA     105.6mA    67.38mA
-1.03V    46.49mA    68.03mA    36.42mA
-962mV    26.1mA     40.41mA    23.27mA
-894mV    17.51mA    23.47mA    18.69mA
-792mV    12.55mA    12.82mA    14.46mA
-350mV    2.336mA    2.453mA    2.152mA
1.452V    -6.889mA   -7.575mA   -5.703mA
1.656V    -9.875mA   -12.24mA   -7.853mA
1.894V    -23.92mA   -26.09mA   -23.36mA
2.03V     -35.21mA   -41.82mA   -35.65mA
2.132V    -50.4mA    -70.76mA   -46.27mA
2.2V      -72.66mA   -101.7mA   -58.35mA
[Ramp]
| variable   typ   min   max
dV/dt_r   0.141/0.177n   0.143/0.191n   0.126/0.172n
dV/dt_f   0.207/0.141n   0.203/0.166n   0.205/0.130n
R_load = 50.000
[Rising Waveform]
R_fixture= 50.000
V_fixture= 0.0
V_fixture_min= 0.0
V_fixture_max= 0.0
|time   V(typ)   V(min)   V(max)
0s        1.878uV    9.986uV    847.8nV
389ps     259.1uV    121.5uV    885.4uV
495ps     3.319mV    -95.36uV   87.49mV
582ps     83.23mV    785.1uV    152.1mV
620ps     119.8mV    21.78mV    169.4mV
690ps     171.4mV    87.04mV    189.3mV
809ps     213.4mV    176.4mV    203.8mV
911ps     226.5mV    212mV      208.1mV
1.039ns   232.3mV    229.3mV    209.9mV
10ns      234.9mV    237.8mV    210.7mV
[Rising Waveform]
R_fixture= 50.000
V_fixture= 0.550
V_fixture_min= 0.534
V_fixture_max= 0.568
|time   V(typ)   V(min)   V(max)
0s        376.7mV    364.2mV    395.6mV
404ps     376.8mV    364.3mV    398.5mV
458ps     376.8mV    364.4mV    439.9mV
496ps     383.8mV    364.1mV    498.1mV
582ps     468.2mV    368.3mV    609.6mV
651ps     568.1mV    418.9mV    650.7mV
738ps     632.9mV    528.5mV    674.3mV
848ps     664.3mV    613.8mV    685.3mV
1.011ns   676.8mV    650.9mV    689.5mV
10ns      680mV      661.3mV    690.6mV
[Falling Waveform]
R_fixture= 50.000
V_fixture= 0.550
V_fixture_min= 0.534
V_fixture_max= 0.568
|time   V(typ)   V(min)   V(max)
0s        680mV      661.3mV    690.6mV
396ps     680.2mV    661.3mV    689mV
420ps     680.6mV    661.3mV    663.1mV
500ps     669.9mV    662.2mV    509.8mV
578ps     533.4mV    658mV      441.7mV
648ps     448.1mV    581.9mV    416.7mV
753ps     399.9mV    442.5mV    402.5mV
828ps     387.6mV    401.5mV    398.9mV
943ps     380.4mV    377.2mV    396.7mV
10ns      376.7mV    364.2mV    395.6mV
[Falling Waveform]
R_fixture= 50.000
V_fixture= 0.0
V_fixture_min= 0.0
V_fixture_max= 0.0
|time   V(typ)   V(min)   V(max)
0s        234.9mV    237.8mV    210.7mV
392ps     235.3mV    237.9mV    209.6mV
491ps     228mV      239.1mV    79.87mV
568ps     116.6mV    235.4mV    31.07mV
602ps     77.08mV    213mV      20.8mV
638ps     49.81mV    164.2mV    13.66mV
733ps     16.68mV    57.44mV    4.701mV
812ps     7.039mV    23.79mV    2.026mV
922ps     2.287mV    7.54mV     686.5uV
10ns      1.889uV    9.999uV    863.1nV
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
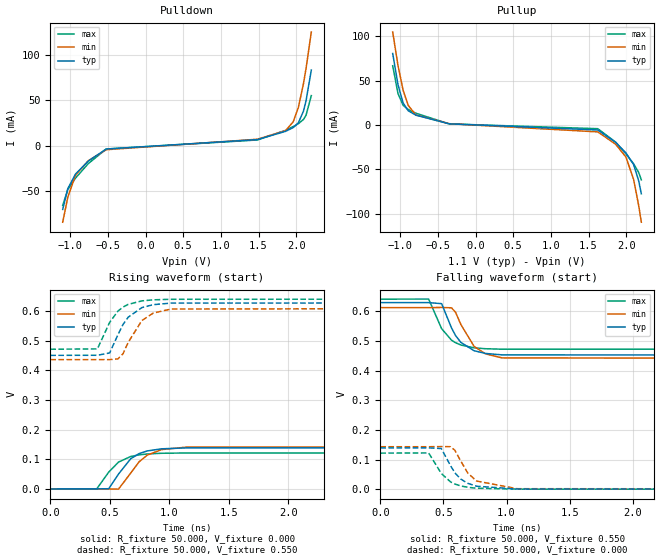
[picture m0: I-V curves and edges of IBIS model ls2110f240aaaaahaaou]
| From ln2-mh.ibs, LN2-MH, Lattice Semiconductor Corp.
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|   Model ls2110f240aaaaahaaou
[Model] ls2110f240aaaaahaaou
Model_type Output
Polarity   Non-Inverting
Enable   Active-High
Vmeas =  0.550V
Cref =  20.000pF
Rref =  50.000
Vref =  0.600V
C_comp   2.000pF   1.500pF   2.500pF
[Temperature Range]   25.000   0.125k   -40.000
[Voltage Range]   1.100V   1.070V   1.130V
[C Comp Corner]
C_comp   2.000pF   1.500pF   2.500pF
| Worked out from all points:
|   slope of the pulldown table from 0 to 0.165 V, typ, clamps not added: 226 ohm
|   slope of the pullup table from 0 to 0.165 V, typ, clamps not added: 285 ohm
|   rising waveform, R_fixture 50.000, V_fixture 0.000: 20-80 % time 167ps typ, 178ps min, 160ps max; typ from 0 V to 0.139 V
|   rising waveform, R_fixture 50.000, V_fixture 0.550: 20-80 % time 155ps typ, 164ps min, 147ps max; typ from 0.451 V to 0.629 V
|   falling waveform, R_fixture 50.000, V_fixture 0.550: 20-80 % time 140ps typ, 153ps min, 134ps max; typ from 0.629 V to 0.451 V
|   falling waveform, R_fixture 50.000, V_fixture 0.000: 20-80 % time 136ps typ, 144ps min, 131ps max; typ from 0.139 V to 0 V
[Pulldown]
|Voltage   I(typ)   I(min)   I(max)
-1.1V     -70.48mA   -84.6mA    -66.03mA
-1.032V   -47.41mA   -56.86mA   -48.41mA
-930mV    -31.43mA   -32.77mA   -35.94mA
-760mV    -17.07mA   -16.65mA   -19.85mA
-522mV    -3.767mA   -4.526mA   -3.778mA
1.484V    6.645mA    7.035mA    6.22mA
1.858V    15.77mA    16.54mA    16.82mA
1.96V     19.93mA    26.39mA    21.06mA
2.028V    25.15mA    42.13mA    24.19mA
2.096V    38.09mA    68.49mA    28.9mA
2.13V     49.57mA    85.28mA    33.6mA
2.2V      83.5mA     125.4mA    55.21mA
[Pullup]
|Voltage   I(typ)   I(min)   I(max)
-1.1V     80.58mA    104.8mA    66.79mA
-1.03V    45.48mA    67.07mA    35.51mA
-962mV    24.76mA    39.2mA     22.09mA
-894mV    15.98mA    22.01mA    17.44mA
-792mV    10.99mA    11.2mA     13.21mA
-350mV    1.24mA     1.382mA    1.152mA
1.622V    -5.699mA   -7.846mA   -4.261mA
1.86V     -19.75mA   -21.86mA   -19.47mA
1.996V    -31.64mA   -36.27mA   -32.81mA
2.098V    -44.8mA    -61.65mA   -43.89mA
2.166V    -63.34mA   -91.41mA   -53.85mA
2.2V      -77.72mA   -109.8mA   -62mA
[Ramp]
| variable   typ   min   max
dV/dt_r   83.557m/0.168n   85.808m/0.179n   72.720m/0.160n
dV/dt_f   0.119/0.149n   0.117/0.169n   0.115/0.139n
R_load = 50.000
[Rising Waveform]
R_fixture = 50.000
V_fixture = 0.000
V_fixture_min = 0.000
V_fixture_max = 0.000
|  time   V(typ)   V(min)   V(max)
0s        2.527uV    12.65uV    1.11uV
391ps     313.8uV    161.2uV    496.1uV
491ps     648.9uV    1.369uV    56.67mV
573ps     49.96mV    -797.4uV   90.49mV
676ps     101.9mV    53.62mV    109.4mV
746ps     119.1mV    91.41mV    115mV
815ps     128.2mV    114.1mV    118mV
936ps     135.3mV    132.7mV    120.3mV
1.149ns   138.5mV    141.2mV    121.3mV
10ns      139.1mV    143mV      121.5mV
[Rising Waveform]
R_fixture = 50.000
V_fixture = 0.550
V_fixture_min = 0.534
V_fixture_max = 0.568
|  time   V(typ)   V(min)   V(max)
0s        450.6mV    436.2mV    471.2mV
396ps     450.9mV    436.4mV    472.4mV
499ps     458.8mV    436.2mV    561.9mV
569ps     520.6mV    438.7mV    600.2mV
612ps     555.3mV    456.5mV    613.7mV
655ps     579.4mV    494.6mV    622.6mV
769ps     611.6mV    567.9mV    634.3mV
865ps     621.6mV    593.1mV    637.9mV
1.015ns   626.9mV    606.9mV    639.8mV
10ns      628.9mV    612.1mV    640.5mV
[Falling Waveform]
R_fixture = 50.000
V_fixture = 0.550
V_fixture_min = 0.534
V_fixture_max = 0.568
|  time   V(typ)   V(min)   V(max)
0s        628.9mV    612.1mV    640.5mV
383ps     628.8mV    612mV      640.8mV
486ps     625.3mV    612.5mV    540.9mV
564ps     543.7mV    611.3mV    502.4mV
596ps     518mV      596.5mV    493.7mV
638ps     494.9mV    555.2mV    486mV
743ps     466.6mV    481.3mV    476.4mV
833ps     457.5mV    456.1mV    473.4mV
963ps     452.7mV    442.6mV    471.8mV
10ns      450.6mV    436.2mV    471.2mV
[Falling Waveform]
R_fixture = 50.000
V_fixture = 0.000
V_fixture_min = 0.000
V_fixture_max = 0.000
|  time   V(typ)   V(min)   V(max)
0s        139.1mV    143mV      121.5mV
383ps     139.2mV    143mV      122.2mV
483ps     137mV      143.7mV    53.18mV
556ps     79.69mV    143.1mV    24.71mV
591ps     54.93mV    131.1mV    17.3mV
637ps     34.2mV     95.05mV    10.87mV
693ps     19.58mV    54.37mV    6.235mV
763ps     9.916mV    27.39mV    3.146mV
1.083ns   553.5uV    1.571mV    179.8uV
10ns      2.527uV    12.65uV    1.11uV
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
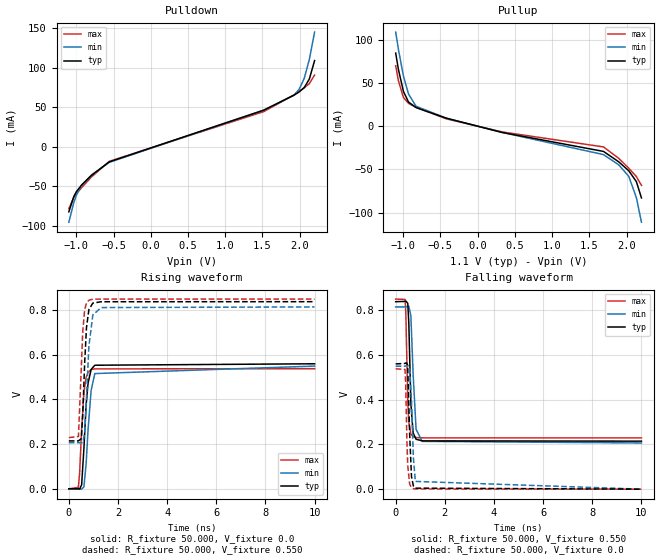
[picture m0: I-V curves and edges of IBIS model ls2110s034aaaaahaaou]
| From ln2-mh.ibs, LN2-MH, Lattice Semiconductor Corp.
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|   Model ls2110s034aaaaahaaou
[Model] ls2110s034aaaaahaaou
Model_type Output
Polarity   Non-Inverting
Enable   Active-High
Vmeas =  0.550V
Cref =  20.000pF
Rref =  50.000
Vref =  0.600V
C_comp   2.000pF   1.500pF   2.500pF
[Temperature Range]   25.000   0.125k   -40.000
[Voltage Range]   1.100V   1.070V   1.130V
[C Comp Corner]
C_comp   2.000pF   1.500pF   2.500pF
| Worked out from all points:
|   slope of the pulldown table from 0 to 0.165 V, typ, clamps not added: 31.9 ohm
|   slope of the pullup table from 0 to 0.165 V, typ, clamps not added: 45.3 ohm
|   rising waveform, R_fixture 50.000, V_fixture 0.0: 20-80 % time 174ps typ, 204ps min, 156ps max; typ from 0 V to 0.56 V
|   rising waveform, R_fixture 50.000, V_fixture 0.550: 20-80 % time 144ps typ, 167ps min, 127ps max; typ from 0.214 V to 0.837 V
|   falling waveform, R_fixture 50.000, V_fixture 0.550: 20-80 % time 93.5ps typ, 122ps min, 79.5ps max; typ from 0.837 V to 0.214 V
|   falling waveform, R_fixture 50.000, V_fixture 0.0: 20-80 % time 85ps typ, 105ps min, 75.3ps max; typ from 0.56 V to 0 V
[Pulldown]
|Voltage   I(typ)   I(min)   I(max)
-1.1V     -82.08mA   -95.12mA   -78.17mA
-1.032V   -62.45mA   -69.98mA   -63.64mA
-998mV    -56.5mA    -61mA      -59.15mA
-930mV    -48.3mA    -48.87mA   -51.6mA
-794mV    -35.85mA   -35.33mA   -37.78mA
-556mV    -18.82mA   -19.52mA   -18.2mA
1.518V    46.44mA    46.55mA    44.66mA
1.926V    65.51mA    65.6mA     65.84mA
1.994V    69.6mA     72.99mA    70.2mA
2.062V    75.1mA     86.91mA    74.73mA
2.13V     85.87mA    110.7mA    80.09mA
2.2V      109.1mA    145.1mA    90.74mA
[Pullup]
|Voltage   I(typ)   I(min)   I(max)
-1.1V     84.75mA    109.1mA    70.17mA
-1.064V   66.08mA    89.38mA    52.9mA
-996mV    40.39mA    58.24mA    33.32mA
-928mV    28.1mA     37.38mA    26.55mA
-826mV    21.65mA    23.15mA    21.93mA
-418mV    9.287mA    9.351mA    8.54mA
330mV     -7.158mA   -7.159mA   -6.543mA
1.69V     -29.12mA   -32.79mA   -23.92mA
1.894V    -41.11mA   -44.56mA   -37.08mA
2.03V     -51.55mA   -58.07mA   -48.59mA
2.132V    -64.19mA   -82.78mA   -58.31mA
2.2V      -82.98mA   -111.1mA   -68.47mA
[Ramp]
| variable   typ   min   max
dV/dt_r   0.336/0.174n   0.330/0.204n   0.323/0.156n
dV/dt_f   0.402/0.103n   0.393/0.140n   0.404/84.966p
R_load = 50.000
[Rising Waveform]
R_fixture= 50.000
V_fixture= 0.0
V_fixture_min= 0.0
V_fixture_max= 0.0
|time   V(typ)   V(min)   V(max)
0s        969.9nV    5.215uV    445nV
388ps     -74.28uV   53.81uV    6.259mV
439ps     -1.601mV   63.17uV    69.07mV
522ps     18.08mV    -1.6mV     265.8mV
614ps     180.1mV    8.28mV     431.6mV
704ps     374.6mV    111.6mV    498.6mV
783ps     472.6mV    264.9mV    521.4mV
907ps     533.5mV    439.4mV    533.4mV
1.057ns   553mV      515.7mV    536.7mV
10ns      559.5mV    549.2mV    537.6mV
[Rising Waveform]
R_fixture= 50.000
V_fixture= 0.550
V_fixture_min= 0.534
V_fixture_max= 0.568
|time   V(typ)   V(min)   V(max)
0s        214.4mV    206.4mV    229.1mV
392ps     214.3mV    206.4mV    234mV
510ps     224.6mV    205.6mV    547mV
566ps     330mV      205.9mV    703mV
645ps     564.7mV    248.6mV    800.6mV
719ps     721.9mV    408.6mV    831.5mV
816ps     801.5mV    637.8mV    844.1mV
977ps     831.1mV    778mV      848.3mV
1.316ns   837.1mV    811.1mV    849.1mV
10ns      837.4mV    813.9mV    849.1mV
[Falling Waveform]
R_fixture= 50.000
V_fixture= 0.550
V_fixture_min= 0.534
V_fixture_max= 0.568
|time   V(typ)   V(min)   V(max)
0s        837.4mV    813.9mV    849.1mV
384ps     838.6mV    814mV      847.4mV
414ps     840.2mV    814.4mV    778.3mV
492ps     829.8mV    816.9mV    389.2mV
534ps     740.6mV    816.9mV    299.8mV
618ps     381.7mV    774.1mV    246.1mV
709ps     251.2mV    515.1mV    234.1mV
829ps     222.9mV    267.3mV    230.6mV
1.079ns   215.8mV    213.4mV    229.3mV
10ns      214.4mV    206.4mV    229.1mV
[Falling Waveform]
R_fixture= 50.000
V_fixture= 0.0
V_fixture_min= 0.0
V_fixture_max= 0.0
|time   V(typ)   V(min)   V(max)
0s        559.5mV    549.2mV    537.5mV
379ps     561.5mV    549.4mV    534.7mV
403ps     563.3mV    549.8mV    481.1mV
456ps     563.6mV    552.1mV    218.1mV
491ps     537.6mV    554mV      105.2mV
568ps     244.6mV    542.1mV    22.8mV
643ps     56.33mV    396.7mV    6.4mV
719ps     14.5mV     142.9mV    2.187mV
799ps     4.567mV    34.67mV    883.7uV
10ns      979.3nV    5.217uV    457.3nV
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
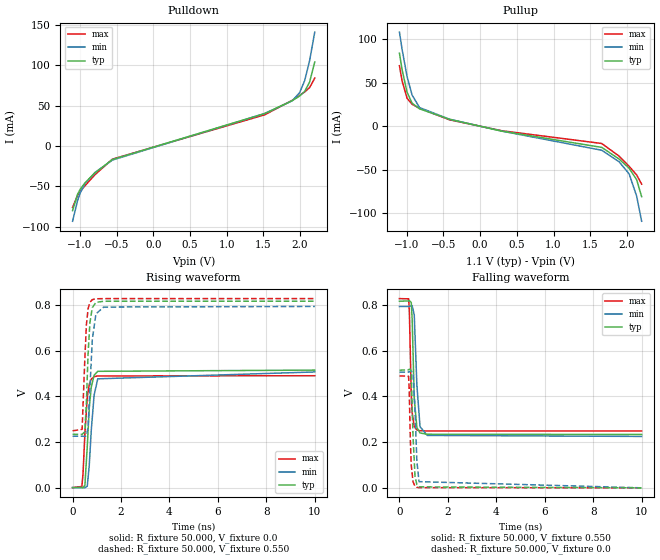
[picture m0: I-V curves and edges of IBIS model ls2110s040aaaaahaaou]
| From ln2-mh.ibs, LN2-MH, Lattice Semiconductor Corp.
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|   Model ls2110s040aaaaahaaou
[Model] ls2110s040aaaaahaaou
Model_type Output
Polarity   Non-Inverting
Enable   Active-High
Vmeas =  0.550V
Cref =  20.000pF
Rref =  50.000
Vref =  0.600V
C_comp   2.000pF   1.500pF   2.500pF
[Temperature Range]   25.000   0.125k   -40.000
[Voltage Range]   1.100V   1.070V   1.130V
[C Comp Corner]
C_comp   2.000pF   1.500pF   2.500pF
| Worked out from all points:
|   slope of the pulldown table from 0 to 0.165 V, typ, clamps not added: 36.9 ohm
|   slope of the pullup table from 0 to 0.165 V, typ, clamps not added: 52.6 ohm
|   rising waveform, R_fixture 50.000, V_fixture 0.0: 20-80 % time 165ps typ, 198ps min, 152ps max; typ from 0 V to 0.515 V
|   rising waveform, R_fixture 50.000, V_fixture 0.550: 20-80 % time 135ps typ, 161ps min, 124ps max; typ from 0.233 V to 0.816 V
|   falling waveform, R_fixture 50.000, V_fixture 0.550: 20-80 % time 94.4ps typ, 122ps min, 82ps max; typ from 0.816 V to 0.233 V
|   falling waveform, R_fixture 50.000, V_fixture 0.0: 20-80 % time 85.2ps typ, 105ps min, 77.8ps max; typ from 0.515 V to 0 V
[Pulldown]
|Voltage   I(typ)   I(min)   I(max)
-1.1V     -80.13mA   -93.34mA   -76.18mA
-1.032V   -59.99mA   -67.81mA   -61.23mA
-998mV    -53.9mA    -58.64mA   -56.69mA
-930mV    -45.61mA   -46.27mA   -49.16mA
-794mV    -33.29mA   -32.75mA   -35.47mA
-556mV    -16.64mA   -17.34mA   -16.19mA
1.518V    40.3mA     40.42mA    38.8mA
1.892V    56.34mA    56.06mA    56.7mA
1.994V    62.1mA     66.32mA    62.84mA
2.062V    67.75mA    81.17mA    67.18mA
2.13V     79.49mA    106.1mA    72.58mA
2.2V      104.4mA    141.5mA    84.35mA
[Pullup]
|Voltage   I(typ)   I(min)   I(max)
-1.1V     84mA       108.3mA    69.59mA
-1.064V   65.2mA     88.5mA     52.17mA
-996mV    39.18mA    57.12mA    32.26mA
-928mV    26.62mA    35.99mA    25.36mA
-826mV    20.08mA    21.54mA    20.71mA
-418mV    8.066mA    8.138mA    7.463mA
296mV     -5.553mA   -5.54mA    -5.094mA
1.656V    -24.22mA   -27.49mA   -19.73mA
1.894V    -37.66mA   -40.83mA   -34.34mA
2.03V     -48.25mA   -54.74mA   -45.99mA
2.132V    -61.34mA   -80.24mA   -55.88mA
2.2V      -80.8mA    -109.1mA   -66.39mA
[Ramp]
| variable   typ   min   max
dV/dt_r   0.309/0.165n   0.304/0.198n   0.294/0.153n
dV/dt_f   0.379/0.105n   0.371/0.142n   0.381/86.868p
R_load = 50.000
[Rising Waveform]
R_fixture= 50.000
V_fixture= 0.0
V_fixture_min= 0.0
V_fixture_max= 0.0
|time   V(typ)   V(min)   V(max)
0s        1.078uV    5.78uV     493nV
385ps     -28.86uV   54.59uV    4.923mV
432ps     -1.132mV   78.29uV    60.73mV
510ps     10.95mV    -1.11mV    238.2mV
607ps     179.2mV    6.281mV    396.7mV
690ps     349.4mV    97.24mV    452.7mV
770ps     439.3mV    248mV      474.8mV
890ps     492.1mV    405mV      485.9mV
1.04ns    509.3mV    476.4mV    489.1mV
10ns      514.6mV    506.5mV    489.9mV
[Rising Waveform]
R_fixture= 50.000
V_fixture= 0.550
V_fixture_min= 0.534
V_fixture_max= 0.568
|time   V(typ)   V(min)   V(max)
0s        233.5mV    224.9mV    248.7mV
394ps     233.3mV    225mV      255mV
508ps     244.1mV    224.2mV    566.2mV
572ps     374.5mV    225.6mV    714.1mV
642ps     588.5mV    267.8mV    783.9mV
717ps     723.2mV    435.8mV    811.8mV
815ps     788mV      648.6mV    823.3mV
965ps     811.2mV    760.7mV    827mV
1.285ns   816.2mV    790.8mV    827.7mV
10ns      816.4mV    793.4mV    827.8mV
[Falling Waveform]
R_fixture= 50.000
V_fixture= 0.550
V_fixture_min= 0.534
V_fixture_max= 0.568
|time   V(typ)   V(min)   V(max)
0s        816.4mV    793.4mV    827.8mV
382ps     817.6mV    793.5mV    826.7mV
411ps     819mV      793.8mV    765.7mV
488ps     810.3mV    796.2mV    406.4mV
526ps     736.8mV    796.6mV    327.8mV
612ps     391.5mV    757mV      268mV
719ps     263.9mV    451.7mV    253.2mV
850ps     240.1mV    267.7mV    249.8mV
1.147ns   234.3mV    229.3mV    248.8mV
10ns      233.5mV    224.9mV    248.7mV
[Falling Waveform]
R_fixture= 50.000
V_fixture= 0.0
V_fixture_min= 0.0
V_fixture_max= 0.0
|time   V(typ)   V(min)   V(max)
0s        514.6mV    506.5mV    489.9mV
377ps     516.5mV    506.7mV    488mV
401ps     518.3mV    507.1mV    437mV
450ps     519.2mV    509.1mV    210.6mV
489ps     492.7mV    511.3mV    99.28mV
562ps     223.1mV    502.1mV    25.92mV
644ps     49.62mV    338.9mV    6.827mV
719ps     14.41mV    118mV      2.382mV
809ps     4.17mV     27.08mV    831.6uV
10ns      1.088uV    5.784uV    505.9nV
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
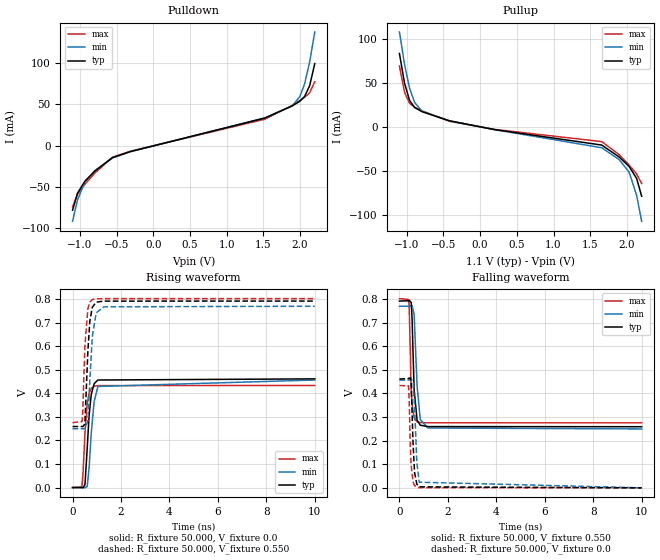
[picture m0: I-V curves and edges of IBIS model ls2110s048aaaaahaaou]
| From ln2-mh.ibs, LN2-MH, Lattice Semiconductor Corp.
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|   Model ls2110s048aaaaahaaou
[Model] ls2110s048aaaaahaaou
Model_type Output
Polarity   Non-Inverting
Enable   Active-High
Vmeas =  0.550V
Cref =  20.000pF
Rref =  50.000
Vref =  0.600V
C_comp   2.000pF   1.500pF   2.500pF
[Temperature Range]   25.000   0.125k   -40.000
[Voltage Range]   1.100V   1.070V   1.130V
[C Comp Corner]
C_comp   2.000pF   1.500pF   2.500pF
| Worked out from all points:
|   slope of the pulldown table from 0 to 0.165 V, typ, clamps not added: 44.4 ohm
|   slope of the pullup table from 0 to 0.165 V, typ, clamps not added: 63.1 ohm
|   rising waveform, R_fixture 50.000, V_fixture 0.0: 20-80 % time 168ps typ, 204ps min, 150ps max; typ from 0 V to 0.461 V
|   rising waveform, R_fixture 50.000, V_fixture 0.550: 20-80 % time 138ps typ, 167ps min, 121ps max; typ from 0.259 V to 0.791 V
|   falling waveform, R_fixture 50.000, V_fixture 0.550: 20-80 % time 102ps typ, 134ps min, 85ps max; typ from 0.791 V to 0.259 V
|   falling waveform, R_fixture 50.000, V_fixture 0.0: 20-80 % time 89.9ps typ, 112ps min, 80.7ps max; typ from 0.461 V to 0 V
[Pulldown]
|Voltage   I(typ)   I(min)   I(max)
-1.1V     -78.02mA   -91.42mA   -73.95mA
-1.032V   -57.31mA   -65.45mA   -58.5mA
-930mV    -42.66mA   -43.45mA   -46.38mA
-794mV    -30.47mA   -29.92mA   -32.83mA
-556mV    -14.23mA   -14.95mA   -13.9mA
-318mV    -7.17mA    -7.312mA   -6.76mA
1.518V    33.49mA    33.69mA    32.15mA
1.892V    48.25mA    48.32mA    48.74mA
1.994V    53.77mA    59.12mA    54.52mA
2.062V    59.67mA    75.04mA    58.65mA
2.13V     72.64mA    101.3mA    64.17mA
2.2V      99.43mA    137.7mA    77.46mA
[Pullup]
|Voltage   I(typ)   I(min)   I(max)
-1.1V     83.26mA    107.6mA    68.98mA
-1.03V    49.39mA    70.69mA    39.04mA
-962mV    30.1mA     43.95mA    26.72mA
-894mV    22.07mA    27.83mA    22.34mA
-792mV    17.23mA    17.69mA    18.14mA
-418mV    6.832mA    6.929mA    6.352mA
194mV     -3.07mA    -3.061mA   -2.816mA
1.656V    -20.62mA   -23.68mA   -16.72mA
1.894V    -34.2mA    -37.13mA   -31.55mA
2.03V     -44.96mA   -51.44mA   -43.37mA
2.132V    -58.52mA   -77.74mA   -53.44mA
2.2V      -78.64mA   -107.1mA   -64.31mA
[Ramp]
| variable   typ   min   max
dV/dt_r   0.277/0.169n   0.274/0.205n   0.260/0.150n
dV/dt_f   0.349/0.115n   0.341/0.159n   0.349/90.328p
R_load = 50.000
[Rising Waveform]
R_fixture= 50.000
V_fixture= 0.0
V_fixture_min= 0.0
V_fixture_max= 0.0
|time   V(typ)   V(min)   V(max)
0s        1.218uV    6.515uV    556.9nV
382ps     14.2uV     58.91uV    3.169mV
432ps     -1.152mV   82.99uV    60.09mV
512ps     12.24mV    -1.156mV   232.6mV
604ps     164.5mV    4.992mV    354.5mV
683ps     306.9mV    83.43mV    399.7mV
773ps     395.4mV    233.1mV    420.7mV
893ps     440.7mV    365.7mV    429.7mV
1.046ns   456.3mV    428.9mV    432.4mV
10ns      461.1mV    456.3mV    433.1mV
[Rising Waveform]
R_fixture= 50.000
V_fixture= 0.550
V_fixture_min= 0.534
V_fixture_max= 0.568
|time   V(typ)   V(min)   V(max)
0s        258.9mV    249.5mV    275.5mV
391ps     258.8mV    249.5mV    279.8mV
421ps     258.2mV    249.6mV    319.9mV
508ps     269.3mV    248.8mV    599mV
633ps     579.3mV    283mV      760.2mV
713ps     705.2mV    453.6mV    786.7mV
815ps     764.8mV    640.9mV    797.4mV
976ps     786.6mV    741.1mV    800.9mV
1.295ns   791mV      766.8mV    801.5mV
10ns      791.2mV    769.2mV    801.6mV
[Falling Waveform]
R_fixture= 50.000
V_fixture= 0.550
V_fixture_min= 0.534
V_fixture_max= 0.568
|time   V(typ)   V(min)   V(max)
0s        791.2mV    769.2mV    801.6mV
384ps     792.4mV    769.3mV    797.9mV
407ps     793.5mV    769.6mV    746.9mV
486ps     785mV      771.9mV    416.4mV
522ps     716.2mV    772.3mV    353.1mV
607ps     415mV      734.9mV    296.3mV
729ps     286.8mV    431.3mV    279.6mV
860ps     265.3mV    290mV      276.5mV
1.169ns   259.5mV    253.5mV    275.6mV
10ns      258.9mV    249.5mV    275.5mV
[Falling Waveform]
R_fixture= 50.000
V_fixture= 0.0
V_fixture_min= 0.0
V_fixture_max= 0.0
|time   V(typ)   V(min)   V(max)
0s        461mV      456.3mV    433.1mV
375ps     462.9mV    456.4mV    432.4mV
399ps     464.6mV    456.8mV    382.1mV
450ps     465.6mV    458.9mV    172.7mV
484ps     444.9mV    460.8mV    93.89mV
562ps     188.4mV    451.3mV    25.36mV
624ps     65.98mV    345.1mV    9.768mV
719ps     15.21mV    105.5mV    2.628mV
819ps     4.097mV    23.83mV    801.8uV
10ns      1.23uV     6.522uV    570.2nV
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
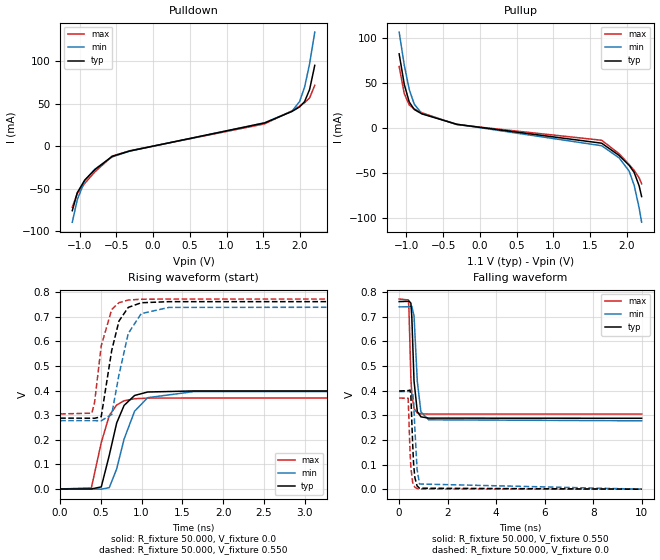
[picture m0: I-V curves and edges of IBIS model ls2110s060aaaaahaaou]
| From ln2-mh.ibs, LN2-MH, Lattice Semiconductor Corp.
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|   Model ls2110s060aaaaahaaou
[Model] ls2110s060aaaaahaaou
Model_type Output
Polarity   Non-Inverting
Enable   Active-High
Vmeas =  0.550V
Cref =  20.000pF
Rref =  50.000
Vref =  0.600V
C_comp   2.000pF   1.500pF   2.500pF
[Temperature Range]   25.000   0.125k   -40.000
[Voltage Range]   1.100V   1.070V   1.130V
[C Comp Corner]
C_comp   2.000pF   1.500pF   2.500pF
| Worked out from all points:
|   slope of the pulldown table from 0 to 0.165 V, typ, clamps not added: 54.8 ohm
|   slope of the pullup table from 0 to 0.165 V, typ, clamps not added: 78.5 ohm
|   rising waveform, R_fixture 50.000, V_fixture 0.0: 20-80 % time 181ps typ, 224ps min, 158ps max; typ from 0 V to 0.398 V
|   rising waveform, R_fixture 50.000, V_fixture 0.550: 20-80 % time 147ps typ, 179ps min, 128ps max; typ from 0.288 V to 0.762 V
|   falling waveform, R_fixture 50.000, V_fixture 0.550: 20-80 % time 115ps typ, 152ps min, 94.6ps max; typ from 0.762 V to 0.288 V
|   falling waveform, R_fixture 50.000, V_fixture 0.0: 20-80 % time 100ps typ, 125ps min, 88.4ps max; typ from 0.398 V to 0 V
[Pulldown]
|Voltage   I(typ)   I(min)   I(max)
-1.1V     -76.12mA   -89.68mA   -72.01mA
-1.032V   -54.89mA   -63.31mA   -56.1mA
-930mV    -39.97mA   -40.86mA   -43.93mA
-794mV    -27.89mA   -27.32mA   -30.51mA
-556mV    -12.02mA   -12.75mA   -11.86mA
-318mV    -5.813mA   -5.931mA   -5.496mA
1.518V    27.25mA    27.47mA    26.2mA
1.892V    40.87mA    41.2mA     41.62mA
1.994V    46.21mA    52.59mA    47.06mA
2.062V    52.43mA    69.57mA    51.01mA
2.13V     66.65mA    96.98mA    56.74mA
2.2V      95.12mA    134.3mA    71.6mA
[Pullup]
|Voltage   I(typ)   I(min)   I(max)
-1.1V     82.53mA    106.8mA    68.41mA
-1.03V    48.37mA    69.71mA    38.15mA
-962mV    28.74mA    42.68mA    25.58mA
-894mV    20.54mA    26.34mA    21.13mA
-792mV    15.67mA    16.06mA    16.92mA
-316mV    4.023mA    4.079mA    3.66mA
1.656V    -17.04mA   -19.86mA   -13.78mA
1.894V    -30.75mA   -33.42mA   -28.82mA
2.03V     -41.68mA   -48.15mA   -40.79mA
2.098V    -49.58mA   -63.85mA   -47.32mA
2.166V    -64.54mA   -89.12mA   -55.66mA
2.2V      -76.53mA   -105.1mA   -62.28mA
[Ramp]
| variable   typ   min   max
dV/dt_r   0.239/0.182n   0.238/0.224n   0.222/0.159n
dV/dt_f   0.314/0.129n   0.307/0.181n   0.314/0.101n
R_load = 50.000
[Rising Waveform]
R_fixture= 50.000
V_fixture= 0.0
V_fixture_min= 0.0
V_fixture_max= 0.0
|time   V(typ)   V(min)   V(max)
0s        1.381uV    7.371uV    628.7nV
383ps     -596.4nV   65.21uV    4.319mV
505ps     8.424mV    -781.9uV   188.9mV
603ps     137.1mV    5.464mV    298.4mV
694ps     268.4mV    82.04mV    341.3mV
785ps     339.7mV    203mV      358.6mV
914ps     380.1mV    316.2mV    366.8mV
1.074ns   394.1mV    370.9mV    369.2mV
1.637ns   398.4mV    395.7mV    369.8mV
10ns      398.5mV    396.5mV    369.8mV
[Rising Waveform]
R_fixture= 50.000
V_fixture= 0.550
V_fixture_min= 0.534
V_fixture_max= 0.568
|time   V(typ)   V(min)   V(max)
0s        287.8mV    277.7mV    304.9mV
389ps     287.7mV    277.7mV    308.2mV
422ps     287.3mV    277.7mV    350.3mV
504ps     293.6mV    277.2mV    581.2mV
633ps     563.2mV    302.5mV    729.6mV
722ps     682.5mV    464mV      757.1mV
836ps     737.9mV    632mV      767.9mV
995ps     756.8mV    712.7mV    771.1mV
1.336ns   761.3mV    737.9mV    771.8mV
10ns      761.5mV    740.2mV    771.8mV
[Falling Waveform]
R_fixture= 50.000
V_fixture= 0.550
V_fixture_min= 0.534
V_fixture_max= 0.568
|time   V(typ)   V(min)   V(max)
0s        761.5mV    740.2mV    771.8mV
382ps     762.6mV    740.3mV    768.2mV
408ps     763.7mV    740.6mV    717mV
484ps     755.3mV    742.5mV    449.3mV
523ps     696.9mV    742.6mV    385.4mV
614ps     438mV      702.8mV    327.1mV
749ps     314.9mV    437.5mV    309mV
897ps     293.7mV    313.6mV    305.8mV
1.219ns   288.4mV    281.6mV    305mV
10ns      287.8mV    277.6mV    304.9mV
[Falling Waveform]
R_fixture= 50.000
V_fixture= 0.0
V_fixture_min= 0.0
V_fixture_max= 0.0
|time   V(typ)   V(min)   V(max)
0s        398.5mV    396.5mV    369.8mV
373ps     400.1mV    396.5mV    369.2mV
446ps     402.4mV    398.7mV    159.1mV
481ps     384.4mV    400.4mV    90.71mV
555ps     189.7mV    394mV      29.12mV
597ps     100.5mV    352mV      15.87mV
648ps     47.01mV    245.8mV    7.847mV
739ps     13.34mV    81.01mV    2.446mV
840ps     3.914mV    20.99mV    777uV
10ns      1.395uV    7.383uV    643.4nV
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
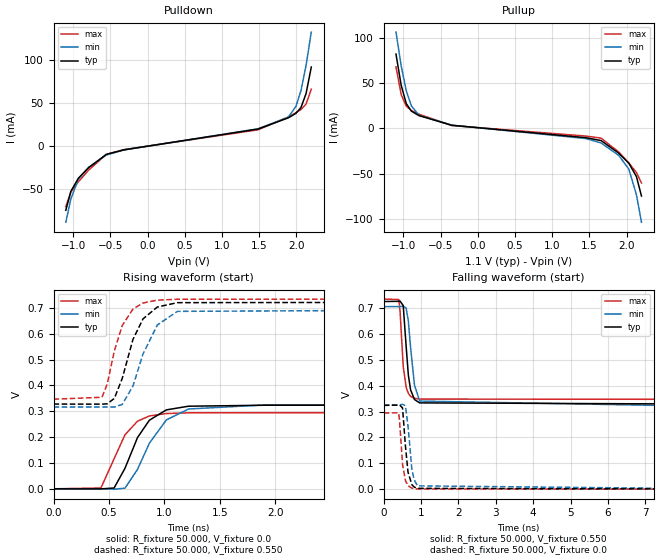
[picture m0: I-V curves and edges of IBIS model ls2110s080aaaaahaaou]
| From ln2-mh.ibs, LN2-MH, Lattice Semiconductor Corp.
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|   Model ls2110s080aaaaahaaou
[Model] ls2110s080aaaaahaaou
Model_type Output
Polarity   Non-Inverting
Enable   Active-High
Vmeas =  0.550V
Cref =  20.000pF
Rref =  50.000
Vref =  0.600V
C_comp   2.000pF   1.500pF   2.500pF
[Temperature Range]   25.000   0.125k   -40.000
[Voltage Range]   1.100V   1.070V   1.130V
[C Comp Corner]
C_comp   2.000pF   1.500pF   2.500pF
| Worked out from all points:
|   slope of the pulldown table from 0 to 0.165 V, typ, clamps not added: 73.8 ohm
|   slope of the pullup table from 0 to 0.165 V, typ, clamps not added: 104 ohm
|   rising waveform, R_fixture 50.000, V_fixture 0.0: 20-80 % time 219ps typ, 254ps min, 191ps max; typ from 0 V to 0.324 V
|   rising waveform, R_fixture 50.000, V_fixture 0.550: 20-80 % time 181ps typ, 211ps min, 153ps max; typ from 0.328 V to 0.725 V
|   falling waveform, R_fixture 50.000, V_fixture 0.550: 20-80 % time 127ps typ, 158ps min, 111ps max; typ from 0.725 V to 0.328 V
|   falling waveform, R_fixture 50.000, V_fixture 0.0: 20-80 % time 111ps typ, 126ps min, 102ps max; typ from 0.324 V to 0 V
[Pulldown]
|Voltage   I(typ)   I(min)   I(max)
-1.1V     -74.32mA   -88.15mA   -70.01mA
-1.032V   -52.39mA   -61.23mA   -53.47mA
-930mV    -37.09mA   -38.15mA   -41.2mA
-794mV    -25.11mA   -24.54mA   -27.91mA
-556mV    -9.618mA   -10.36mA   -9.575mA
-318mV    -4.323mA   -4.427mA   -4.063mA
1.484V    19.76mA    20.03mA    18.88mA
1.892V    32.77mA    33.6mA     33.64mA
1.994V    37.99mA    46.04mA    38.71mA
2.062V    44.81mA    64.59mA    42.51mA
2.13V     60.93mA    93.6mA     48.72mA
2.2V      91.63mA    132.1mA    65.98mA
[Pullup]
|Voltage   I(typ)   I(min)   I(max)
-1.1V     82.02mA    106.3mA    67.94mA
-1.03V    47.49mA    68.99mA    37.3mA
-962mV    27.45mA    41.64mA    24.41mA
-894mV    19.03mA    24.95mA    19.89mA
-792mV    14.11mA    14.46mA    15.68mA
-350mV    3.417mA    3.527mA    3.119mA
1.452V    -10.29mA   -11.24mA   -8.503mA
1.656V    -13.46mA   -16.07mA   -10.79mA
1.894V    -27.35mA   -29.79mA   -26.08mA
2.03V     -38.47mA   -45.05mA   -38.22mA
2.132V    -53.12mA   -73.16mA   -48.65mA
2.2V      -74.7mA    -103.6mA   -60.32mA
[Ramp]
| variable   typ   min   max
dV/dt_r   0.194/0.220n   0.195/0.254n   0.177/0.191n
dV/dt_f   0.266/0.142n   0.261/0.184n   0.264/0.122n
R_load = 50.000
[Rising Waveform]
R_fixture= 50.000
V_fixture= 0.0
V_fixture_min= 0.0
V_fixture_max= 0.0
|time   V(typ)   V(min)   V(max)
0s        1.604uV    8.538uV    728.8nV
427ps     -297.1uV   211.2uV    3.177mV
546ps     3.156mV    -1.375mV   116.2mV
644ps     79.33mV    2.329mV    209.1mV
757ps     198.4mV    75.17mV    261.7mV
864ps     265.5mV    176.6mV    281.9mV
1.017ns   305.5mV    266.7mV    291.4mV
1.217ns   319.7mV    308.9mV    294.1mV
1.907ns   323.5mV    324.7mV    294.6mV
10ns      323.6mV    325mV      294.6mV
[Rising Waveform]
R_fixture= 50.000
V_fixture= 0.550
V_fixture_min= 0.534
V_fixture_max= 0.568
|time   V(typ)   V(min)   V(max)
0s        328mV      316.5mV    346.8mV
437ps     327.7mV    316.7mV    354.3mV
484ps     328.9mV    316.4mV    405.7mV
548ps     349.9mV    316.5mV    533.1mV
619ps     426.7mV    326.4mV    631.7mV
716ps     578.3mV    397.6mV    695.8mV
807ps     658mV      522.5mV    719.2mV
936ps     703.7mV    634.1mV    730.3mV
1.117ns   720.5mV    686.8mV    733.7mV
10ns      724.9mV    705.1mV    734.4mV
[Falling Waveform]
R_fixture= 50.000
V_fixture= 0.550
V_fixture_min= 0.534
V_fixture_max= 0.568
|time   V(typ)   V(min)   V(max)
0s        724.9mV    705.1mV    734.4mV
405ps     725.7mV    705.2mV    732.5mV
437ps     726.6mV    705.4mV    687.7mV
522ps     709.2mV    707mV      474.1mV
600ps     552.1mV    699.4mV    393.9mV
659ps     440.4mV    649.6mV    369.9mV
719ps     383.6mV    546.9mV    358.5mV
823ps     346.3mV    401.8mV    350.9mV
963ps     333.3mV    340.3mV    348.1mV
10ns      328mV      316.5mV    346.8mV
[Falling Waveform]
R_fixture= 50.000
V_fixture= 0.0
V_fixture_min= 0.0
V_fixture_max= 0.0
|time   V(typ)   V(min)   V(max)
0s        323.6mV    325mV      294.6mV
398ps     324.9mV    325.1mV    294.7mV
421ps     325.8mV    325.4mV    269.2mV
504ps     313.9mV    327.8mV    95.7mV
581ps     166.8mV    322.3mV    33.12mV
650ps     65.74mV    243.7mV    13.47mV
753ps     17.37mV    77.33mV    3.868mV
813ps     8.474mV    36.65mV    1.995mV
903ps     3.178mV    12.75mV    823uV
10ns      1.614uV    8.545uV    744.1nV
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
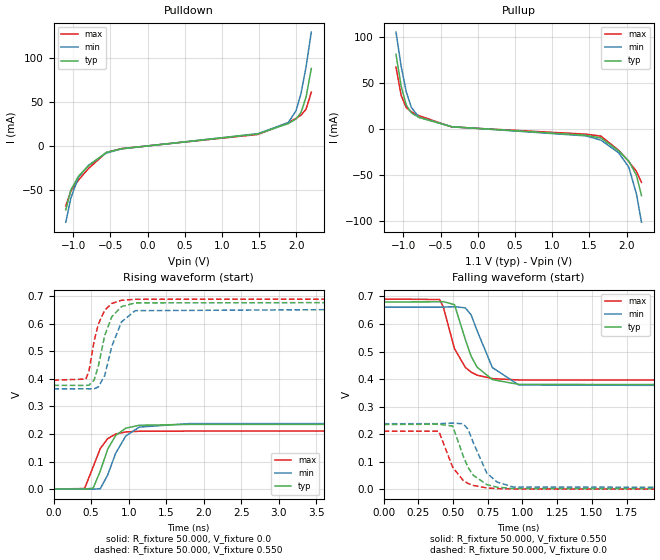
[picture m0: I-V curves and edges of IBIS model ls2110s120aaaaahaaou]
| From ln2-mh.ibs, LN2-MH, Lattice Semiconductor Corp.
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|   Model ls2110s120aaaaahaaou
[Model] ls2110s120aaaaahaaou
Model_type Output
Polarity   Non-Inverting
Enable   Active-High
Vmeas =  0.550V
Cref =  20.000pF
Rref =  50.000
Vref =  0.600V
C_comp   2.000pF   1.500pF   2.500pF
[Temperature Range]   25.000   0.125k   -40.000
[Voltage Range]   1.100V   1.070V   1.130V
[C Comp Corner]
C_comp   2.000pF   1.500pF   2.500pF
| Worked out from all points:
|   slope of the pulldown table from 0 to 0.165 V, typ, clamps not added: 108 ohm
|   slope of the pullup table from 0 to 0.165 V, typ, clamps not added: 156 ohm
|   rising waveform, R_fixture 50.000, V_fixture 0.0: 20-80 % time 207ps typ, 237ps min, 189ps max; typ from 0 V to 0.235 V
|   rising waveform, R_fixture 50.000, V_fixture 0.550: 20-80 % time 172ps typ, 199ps min, 153ps max; typ from 0.377 V to 0.68 V
|   falling waveform, R_fixture 50.000, V_fixture 0.550: 20-80 % time 133ps typ, 156ps min, 123ps max; typ from 0.68 V to 0.377 V
|   falling waveform, R_fixture 50.000, V_fixture 0.0: 20-80 % time 120ps typ, 131ps min, 115ps max; typ from 0.235 V to 0 V
[Pulldown]
|Voltage   I(typ)   I(min)   I(max)
-1.1V     -72.47mA   -86.44mA   -68.13mA
-1.032V   -50.01mA   -59.13mA   -51.09mA
-930mV    -34.39mA   -35.58mA   -38.74mA
-794mV    -22.52mA   -21.93mA   -25.57mA
-556mV    -7.388mA   -8.135mA   -7.523mA
-352mV    -3.262mA   -3.386mA   -3.076mA
1.484V    13.54mA    13.83mA    12.96mA
1.892V    25.3mA     26.48mA    26.4mA
1.994V    30.4mA     39.74mA    31.14mA
2.062V    37.79mA    59.46mA    34.81mA
2.13V     55.42mA    89.57mA    41.52mA
2.2V      87.69mA    128.9mA    60.76mA
[Pullup]
|Voltage   I(typ)   I(min)   I(max)
-1.1V     81.3mA     105.6mA    67.38mA
-1.03V    46.49mA    68.03mA    36.42mA
-962mV    26.1mA     40.41mA    23.27mA
-894mV    17.51mA    23.47mA    18.69mA
-792mV    12.55mA    12.82mA    14.46mA
-350mV    2.336mA    2.453mA    2.152mA
1.452V    -6.889mA   -7.575mA   -5.703mA
1.656V    -9.875mA   -12.24mA   -7.853mA
1.894V    -23.92mA   -26.09mA   -23.36mA
2.03V     -35.21mA   -41.82mA   -35.65mA
2.132V    -50.4mA    -70.76mA   -46.27mA
2.2V      -72.66mA   -101.7mA   -58.35mA
[Ramp]
| variable   typ   min   max
dV/dt_r   0.141/0.207n   0.143/0.238n   0.126/0.189n
dV/dt_f   0.207/0.148n   0.203/0.182n   0.205/0.133n
R_load = 50.000
[Rising Waveform]
R_fixture= 50.000
V_fixture= 0.0
V_fixture_min= 0.0
V_fixture_max= 0.0
|time   V(typ)   V(min)   V(max)
0s        1.878uV    9.986uV    847.8nV
413ps     17.34uV    180.9uV    1.734mV
527ps     2.935mV    -559.6uV   80.35mV
622ps     65.18mV    1.016mV    146.9mV
721ps     145mV      51.02mV    183.1mV
826ps     194.3mV    129.4mV    199.8mV
961ps     221.2mV    192.7mV    207.4mV
1.142ns   231.8mV    225.1mV    210mV
1.797ns   234.9mV    237.7mV    210.7mV
10ns      234.9mV    237.8mV    210.7mV
[Rising Waveform]
R_fixture= 50.000
V_fixture= 0.550
V_fixture_min= 0.534
V_fixture_max= 0.568
|time   V(typ)   V(min)   V(max)
0s        376.7mV    364.2mV    395.6mV
430ps     376.6mV    364.4mV    399.7mV
471ps     377.4mV    364.3mV    427.9mV
540ps     395.8mV    364.3mV    537.3mV
597ps     447.1mV    371.3mV    599.9mV
681ps     558mV      412.2mV    650.1mV
776ps     626.5mV    519.2mV    674.6mV
905ps     663.2mV    607.6mV    686.1mV
1.087ns   676.7mV    648.4mV    689.8mV
10ns      680mV      661.3mV    690.6mV
[Falling Waveform]
R_fixture= 50.000
V_fixture= 0.550
V_fixture_min= 0.534
V_fixture_max= 0.568
|time   V(typ)   V(min)   V(max)
0s        680mV      661.3mV    690.6mV
403ps     680.6mV    661.4mV    689mV
430ps     681.2mV    661.5mV    661mV
510ps     670.4mV    662.8mV    510.5mV
588ps     543.8mV    658.7mV    442.6mV
630ps     482.5mV    633.1mV    425.1mV
673ps     443.1mV    575.7mV    414.1mV
783ps     398mV      441.7mV    401.6mV
973ps     380.5mV    378.7mV    396.7mV
10ns      376.7mV    364.2mV    395.6mV
[Falling Waveform]
R_fixture= 50.000
V_fixture= 0.0
V_fixture_min= 0.0
V_fixture_max= 0.0
|time   V(typ)   V(min)   V(max)
0s        234.9mV    237.8mV    210.7mV
397ps     235.9mV    237.9mV    210.5mV
497ps     229.4mV    240.1mV    79.58mV
573ps     120.2mV    237.4mV    31.48mV
608ps     78.83mV    217.4mV    20.8mV
644ps     51.17mV    170.7mV    13.71mV
743ps     16.45mV    58.38mV    4.538mV
817ps     7.383mV    25.83mV    2.078mV
933ps     2.293mV    7.767mV    679.8uV
10ns      1.89uV     9.999uV    863.4nV
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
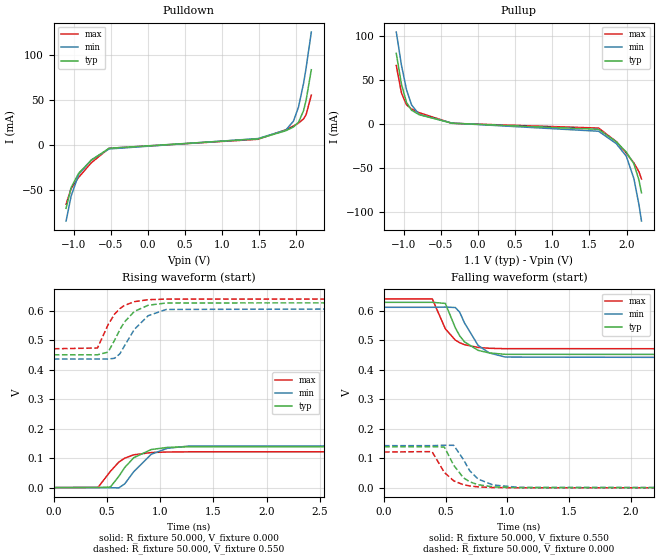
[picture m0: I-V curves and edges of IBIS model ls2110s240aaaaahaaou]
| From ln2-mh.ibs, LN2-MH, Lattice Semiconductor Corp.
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|   Model ls2110s240aaaaahaaou
[Model] ls2110s240aaaaahaaou
Model_type Output
Polarity   Non-Inverting
Enable   Active-High
Vmeas =  0.550V
Cref =  20.000pF
Rref =  50.000
Vref =  0.600V
C_comp   2.000pF   1.500pF   2.500pF
[Temperature Range]   25.000   0.125k   -40.000
[Voltage Range]   1.100V   1.070V   1.130V
[C Comp Corner]
C_comp   2.000pF   1.500pF   2.500pF
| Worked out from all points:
|   slope of the pulldown table from 0 to 0.165 V, typ, clamps not added: 226 ohm
|   slope of the pullup table from 0 to 0.165 V, typ, clamps not added: 285 ohm
|   rising waveform, R_fixture 50.000, V_fixture 0.000: 20-80 % time 197ps typ, 221ps min, 177ps max; typ from 0 V to 0.139 V
|   rising waveform, R_fixture 50.000, V_fixture 0.550: 20-80 % time 187ps typ, 211ps min, 164ps max; typ from 0.451 V to 0.629 V
|   falling waveform, R_fixture 50.000, V_fixture 0.550: 20-80 % time 143ps typ, 160ps min, 135ps max; typ from 0.629 V to 0.451 V
|   falling waveform, R_fixture 50.000, V_fixture 0.000: 20-80 % time 136ps typ, 144ps min, 131ps max; typ from 0.139 V to 0 V
[Pulldown]
|Voltage   I(typ)   I(min)   I(max)
-1.1V     -70.48mA   -84.6mA    -66.03mA
-1.032V   -47.41mA   -56.86mA   -48.41mA
-930mV    -31.43mA   -32.77mA   -35.94mA
-760mV    -17.07mA   -16.65mA   -19.85mA
-522mV    -3.767mA   -4.526mA   -3.778mA
1.484V    6.645mA    7.035mA    6.22mA
1.858V    15.77mA    16.54mA    16.82mA
1.96V     19.93mA    26.39mA    21.06mA
2.028V    25.15mA    42.13mA    24.19mA
2.096V    38.09mA    68.49mA    28.9mA
2.13V     49.57mA    85.28mA    33.6mA
2.2V      83.5mA     125.4mA    55.21mA
[Pullup]
|Voltage   I(typ)   I(min)   I(max)
-1.1V     80.58mA    104.8mA    66.79mA
-1.03V    45.48mA    67.07mA    35.51mA
-962mV    24.76mA    39.2mA     22.09mA
-894mV    15.98mA    22.01mA    17.44mA
-792mV    10.99mA    11.2mA     13.21mA
-350mV    1.24mA     1.382mA    1.152mA
1.622V    -5.699mA   -7.846mA   -4.261mA
1.86V     -19.75mA   -21.86mA   -19.47mA
1.996V    -31.64mA   -36.27mA   -32.81mA
2.098V    -44.8mA    -61.65mA   -43.89mA
2.166V    -63.34mA   -91.41mA   -53.85mA
2.2V      -77.72mA   -109.8mA   -62mA
[Ramp]
| variable   typ   min   max
dV/dt_r   83.559m/0.197n   85.807m/0.221n   72.721m/0.178n
dV/dt_f   0.119/0.155n   0.117/0.182n   0.115/0.142n
R_load = 50.000
[Rising Waveform]
R_fixture = 50.000
V_fixture = 0.000
V_fixture_min = 0.000
V_fixture_max = 0.000
|  time   V(typ)   V(min)   V(max)
0s        2.527uV    12.65uV    1.11uV
416ps     35.5uV     231.2uV    946.9uV
531ps     1.928mV    -628.6uV   55.05mV
611ps     38.24mV    -847uV     86.8mV
666ps     68.2mV     12.7mV     99.89mV
751ps     101.5mV    54.08mV    111.3mV
916ps     129.3mV    113.3mV    119.1mV
1.067ns   136.4mV    133.4mV    120.8mV
1.267ns   138.6mV    141mV      121.4mV
10ns      139.1mV    143mV      121.5mV
[Rising Waveform]
R_fixture = 50.000
V_fixture = 0.550
V_fixture_min = 0.534
V_fixture_max = 0.568
|  time   V(typ)   V(min)   V(max)
0s        450.6mV    436.2mV    471.2mV
410ps     450.7mV    436.4mV    473.7mV
510ps     459.9mV    436.2mV    552.8mV
571ps     500.2mV    439mV      588.9mV
620ps     535.8mV    453.8mV    607.4mV
662ps     561.3mV    479.9mV    618mV
756ps     597.8mV    536.7mV    631mV
886ps     618.8mV    583.3mV    637.6mV
1.056ns   626.5mV    604.6mV    639.8mV
10ns      628.9mV    612.1mV    640.5mV
[Falling Waveform]
R_fixture = 50.000
V_fixture = 0.550
V_fixture_min = 0.534
V_fixture_max = 0.568
|  time   V(typ)   V(min)   V(max)
0s        628.9mV    612.1mV    640.5mV
391ps     629mV      612.1mV    640.7mV
497ps     625.3mV    612.9mV    539.1mV
578ps     542.5mV    611.3mV    500.9mV
613ps     515.7mV    595.8mV    492.1mV
652ps     495.1mV    559.4mV    485.4mV
763ps     466.1mV    482.6mV    476mV
854ps     457.3mV    457.2mV    473.2mV
983ps     452.7mV    443.4mV    471.8mV
10ns      450.6mV    436.2mV    471.2mV
[Falling Waveform]
R_fixture = 50.000
V_fixture = 0.000
V_fixture_min = 0.000
V_fixture_max = 0.000
|  time   V(typ)   V(min)   V(max)
0s        139.1mV    143mV      121.5mV
389ps     139.5mV    143mV      122.9mV
489ps     138.4mV    144.4mV    52.21mV
565ps     76.69mV    144.2mV    23.61mV
643ps     34.17mV    96.36mV    10.75mV
695ps     20.41mV    57.61mV    6.418mV
764ps     10.47mV    29.42mV    3.278mV
884ps     3.408mV    9.69mV     1.056mV
1.093ns   552uV      1.619mV    175.1uV
10ns      2.527uV    12.65uV    1.11uV
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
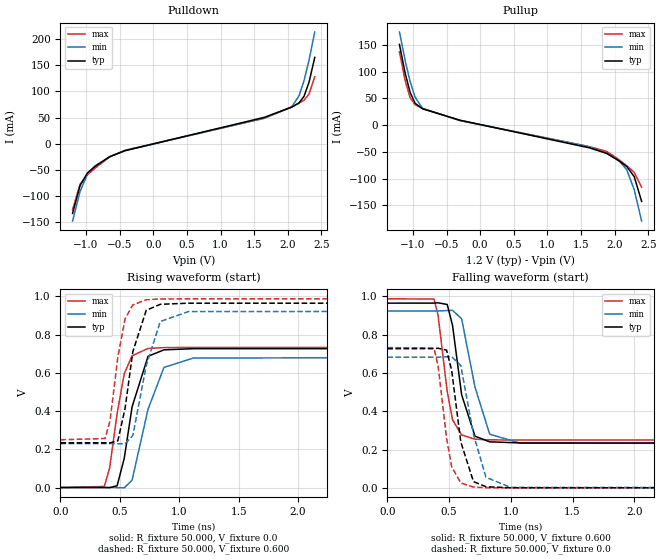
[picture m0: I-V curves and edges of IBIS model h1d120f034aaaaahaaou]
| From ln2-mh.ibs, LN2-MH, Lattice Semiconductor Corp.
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|   Model h1d120f034aaaaahaaou
[Model] h1d120f034aaaaahaaou
Model_type Output
Polarity   Non-Inverting
Enable   Active-High
Vmeas =  0.600V
Cref =  20.000pF
Rref =  50.000
Vref =  0.600V
C_comp   2.000pF   1.500pF   2.500pF
[Temperature Range]   25.000   0.125k   -40.000
[Voltage Range]   1.200V   1.160V   1.240V
[C Comp Corner]
C_comp   2.000pF   1.500pF   2.500pF
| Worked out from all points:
|   slope of the pulldown table from 0 to 0.18 V, typ, clamps not added: 31.9 ohm
|   slope of the pullup table from 0 to 0.18 V, typ, clamps not added: 32.3 ohm
|   rising waveform, R_fixture 50.000, V_fixture 0.0: 20-80 % time 120ps typ, 147ps min, 108ps max; typ from 0 V to 0.727 V
|   rising waveform, R_fixture 50.000, V_fixture 0.600: 20-80 % time 106ps typ, 128ps min, 98.3ps max; typ from 0.234 V to 0.965 V
|   falling waveform, R_fixture 50.000, V_fixture 0.600: 20-80 % time 96.8ps typ, 124ps min, 88.6ps max; typ from 0.965 V to 0.234 V
|   falling waveform, R_fixture 50.000, V_fixture 0.0: 20-80 % time 93.2ps typ, 117ps min, 86.4ps max; typ from 0.727 V to 0 V
[Pulldown]
|Voltage   I(typ)   I(min)   I(max)
-1.2V     -132.9mA   -147.4mA   -126mA
-1.089V   -79.79mA   -91.22mA   -77.41mA
-978mV    -55.54mA   -57.58mA   -59.06mA
-867mV    -43.59mA   -42.26mA   -46.67mA
-645mV    -24.61mA   -24.52mA   -24.84mA
-423mV    -13.34mA   -13.34mA   -12.58mA
1.649V    50.26mA    48.96mA    48.52mA
2.056V    69.68mA    69.95mA    70.1mA
2.167V    77.91mA    91.66mA    77.34mA
2.241V    90.47mA    120.4mA    83.09mA
2.315V    117.4mA    159.6mA    94.54mA
2.4V      164.7mA    213mA      127.8mA
[Pullup]
|Voltage   I(typ)   I(min)   I(max)
-1.2V     151mA      174.1mA    137mA
-1.115V   97.23mA    120.7mA    83.1mA
-1.041V   61.27mA    81.31mA    51.23mA
-967mV    40.99mA    52.5mA     38.23mA
-856mV    30.65mA    31.29mA    31.46mA
-301mV    9.357mA    8.783mA    8.738mA
1.623V    -42.28mA   -40.41mA   -39.95mA
1.882V    -52.67mA   -52.52mA   -49.1mA
2.067V    -66.82mA   -66.78mA   -64.74mA
2.178V    -77.1mA    -83.13mA   -75.68mA
2.289V    -95.85mA   -120.2mA   -87.97mA
2.4V      -142.4mA   -179mA     -115.9mA
[Ramp]
| variable   typ   min   max
dV/dt_r   0.436/0.120n   0.409/0.147n   0.440/0.108n
dV/dt_f   0.439/0.104n   0.421/0.137n   0.444/91.968p
R_load = 50.000
[Rising Waveform]
R_fixture= 50.000
V_fixture= 0.0
V_fixture_min= 0.0
V_fixture_max= 0.0
|time   V(typ)   V(min)   V(max)
0s        1.029uV    5.623uV    470.9nV
369ps     59.13uV    41.78uV    5.59mV
414ps     -534.3uV   69.26uV    102.9mV
477ps     9.354mV    -379.6uV   387.1mV
537ps     153.2mV    -1.694mV   595.9mV
603ps     422.3mV    39.16mV    689.1mV
737ps     686.3mV    409.4mV    727.6mV
871ps     720.2mV    628.2mV    732mV
1.121ns   726.3mV    677.8mV    732.6mV
10ns      726.5mV    682.1mV    732.6mV
[Rising Waveform]
R_fixture= 50.000
V_fixture= 0.600
V_fixture_min= 0.583
V_fixture_max= 0.619
|time   V(typ)   V(min)   V(max)
0s        233.9mV    229.5mV    249.7mV
375ps     234mV      229.6mV    256.4mV
417ps     233.5mV    229.6mV    347.9mV
483ps     244.7mV    229.1mV    682.7mV
544ps     414.3mV    229mV      882.8mV
609ps     710.5mV    271.9mV    955.3mV
722ps     927.1mV    637.2mV    982.3mV
840ps     958.4mV    868.5mV    986.3mV
1.077ns   964.3mV    920.4mV    986.9mV
10ns      964.5mV    923.8mV    986.9mV
[Falling Waveform]
R_fixture= 50.000
V_fixture= 0.600
V_fixture_min= 0.583
V_fixture_max= 0.619
|time   V(typ)   V(min)   V(max)
0s        964.5mV    923.8mV    986.9mV
378ps     964.8mV    923.9mV    986.3mV
411ps     966.3mV    924mV      901.1mV
485ps     957.6mV    925.6mV    503.6mV
528ps     849.1mV    927.3mV    355.9mV
602ps     485.8mV    882.5mV    276mV
710ps     269.8mV    526.3mV    254.1mV
829ps     240.3mV    280.2mV    250.5mV
1.079ns   234.4mV    233mV      249.7mV
10ns      233.9mV    229.5mV    249.7mV
[Falling Waveform]
R_fixture= 50.000
V_fixture= 0.0
V_fixture_min= 0.0
V_fixture_max= 0.0
|time   V(typ)   V(min)   V(max)
0s        726.5mV    682.1mV    732.6mV
378ps     727.1mV    682.1mV    730mV
412ps     728.9mV    682.4mV    633.6mV
480ps     719mV      684.3mV    259.1mV
521ps     614.5mV    685.4mV    110.7mV
595ps     239.7mV    638.6mV    25.31mV
698ps     32.37mV    278.8mV    3.933mV
799ps     5.794mV    54.9mV     661.9uV
1ns       293.5uV    2.638mV    -28.02uV
10ns      1.036uV    5.62uV     480.7nV
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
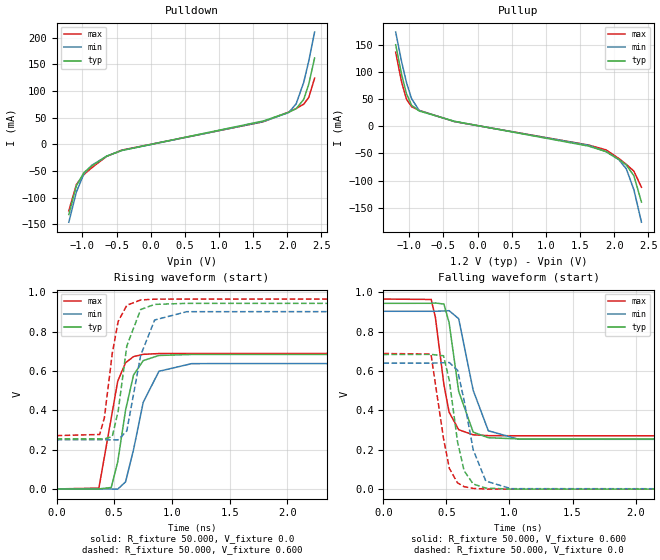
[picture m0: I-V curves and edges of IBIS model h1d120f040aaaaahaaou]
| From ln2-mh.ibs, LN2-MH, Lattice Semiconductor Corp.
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|   Model h1d120f040aaaaahaaou
[Model] h1d120f040aaaaahaaou
Model_type Output
Polarity   Non-Inverting
Enable   Active-High
Vmeas =  0.600V
Cref =  20.000pF
Rref =  50.000
Vref =  0.600V
C_comp   2.000pF   1.500pF   2.500pF
[Temperature Range]   25.000   0.125k   -40.000
[Voltage Range]   1.200V   1.160V   1.240V
[C Comp Corner]
C_comp   2.000pF   1.500pF   2.500pF
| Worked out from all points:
|   slope of the pulldown table from 0 to 0.18 V, typ, clamps not added: 36.9 ohm
|   slope of the pullup table from 0 to 0.18 V, typ, clamps not added: 37.3 ohm
|   rising waveform, R_fixture 50.000, V_fixture 0.0: 20-80 % time 119ps typ, 147ps min, 109ps max; typ from 0 V to 0.684 V
|   rising waveform, R_fixture 50.000, V_fixture 0.600: 20-80 % time 103ps typ, 125ps min, 97.3ps max; typ from 0.255 V to 0.943 V
|   falling waveform, R_fixture 50.000, V_fixture 0.600: 20-80 % time 99.3ps typ, 127ps min, 91.7ps max; typ from 0.943 V to 0.255 V
|   falling waveform, R_fixture 50.000, V_fixture 0.0: 20-80 % time 95.9ps typ, 119ps min, 90ps max; typ from 0.684 V to 0 V
[Pulldown]
|Voltage   I(typ)   I(min)   I(max)
-1.2V     -131.6mA   -146.1mA   -124.7mA
-1.089V   -77.73mA   -89.44mA   -75.31mA
-978mV    -52.9mA    -55.22mA   -56.61mA
-867mV    -40.96mA   -39.73mA   -44.3mA
-645mV    -22.27mA   -22.24mA   -22.7mA
-423mV    -11.57mA   -11.62mA   -10.93mA
1.649V    43.64mA    42.58mA    42.18mA
2.019V    59.89mA    59.32mA    60.3mA
2.13V     66.73mA    75.74mA    67.04mA
2.241V    84.04mA    116.1mA    75.18mA
2.315V    112.8mA    156.3mA    87.92mA
2.4V      161.6mA    210.3mA    123.8mA
[Pullup]
|Voltage   I(typ)   I(min)   I(max)
-1.2V     150mA      173.2mA    136.2mA
-1.115V   95.98mA    119.5mA    81.92mA
-1.041V   59.5mA     79.86mA    49.41mA
-967mV    38.64mA    50.65mA    35.94mA
-856mV    28.09mA    28.99mA    29.17mA
-338mV    9.116mA    8.575mA    8.54mA
1.623V    -36.49mA   -34.96mA   -34.51mA
1.882V    -46.66mA   -46.87mA   -43.48mA
2.067V    -60.85mA   -61.26mA   -59.2mA
2.178V    -71.25mA   -78.35mA   -70.16mA
2.289V    -91.11mA   -116.8mA   -82.62mA
2.4V      -139.5mA   -176.5mA   -112.3mA
[Ramp]
| variable   typ   min   max
dV/dt_r   0.410/0.120n   0.384/0.148n   0.413/0.109n
dV/dt_f   0.414/0.107n   0.397/0.141n   0.418/94.428p
R_load = 50.000
[Rising Waveform]
R_fixture= 50.000
V_fixture= 0.0
V_fixture_min= 0.0
V_fixture_max= 0.0
|time   V(typ)   V(min)   V(max)
0s        1.143uV    6.223uV    521.7nV
367ps     64.71uV    45.66uV    4.168mV
474ps     7.401mV    -312.3uV   360.7mV
530ps     137.5mV    -1.203mV   547.4mV
598ps     400.2mV    35.76mV    641.5mV
667ps     578.6mV    199.3mV    672.7mV
751ps     652.3mV    440.2mV    684.2mV
887ps     678.5mV    598mV      688.2mV
1.171ns   683.5mV    637mV      688.7mV
10ns      683.6mV    639.6mV    688.7mV
[Rising Waveform]
R_fixture= 50.000
V_fixture= 0.600
V_fixture_min= 0.583
V_fixture_max= 0.619
|time   V(typ)   V(min)   V(max)
0s        254.7mV    249.8mV    271mV
374ps     254.8mV    249.9mV    276.9mV
415ps     254.3mV    249.9mV    363.1mV
483ps     266.3mV    249.5mV    689.9mV
534ps     395.2mV    249.6mV    851.5mV
609ps     727.2mV    295.3mV    933.7mV
729ps     912.1mV    679.5mV    960.7mV
850ps     938.1mV    858.9mV    964.6mV
1.129ns   943.4mV    901.1mV    965.2mV
10ns      943.4mV    903.1mV    965.2mV
[Falling Waveform]
R_fixture= 50.000
V_fixture= 0.600
V_fixture_min= 0.583
V_fixture_max= 0.619
|time   V(typ)   V(min)   V(max)
0s        943.4mV    903.1mV    965.1mV
379ps     943.7mV    903.1mV    963.1mV
412ps     945.2mV    903.2mV    873.3mV
480ps     939.7mV    904.6mV    530.1mV
521ps     845.4mV    906.3mV    391.1mV
597ps     496.6mV    865.3mV    301.9mV
712ps     289.6mV    501.8mV    275.9mV
832ps     261.1mV    296.5mV    271.8mV
1.072ns   255.1mV    253.4mV    271mV
10ns      254.7mV    249.8mV    271mV
[Falling Waveform]
R_fixture= 50.000
V_fixture= 0.0
V_fixture_min= 0.0
V_fixture_max= 0.0
|time   V(typ)   V(min)   V(max)
0s        683.6mV    639.6mV    688.7mV
377ps     684.3mV    639.7mV    686.2mV
477ps     677.2mV    641.8mV    256.7mV
523ps     550.9mV    642.7mV    105.2mV
588ps     240.2mV    603.8mV    31.7mV
640ps     93.53mV    450.5mV    12.8mV
712ps     26.24mV    200.3mV    3.789mV
812ps     5.381mV    41.31mV    666.1uV
1.011ns   250.5uV    2.536mV    -52.52uV
10ns      1.151uV    6.222uV    532.6nV
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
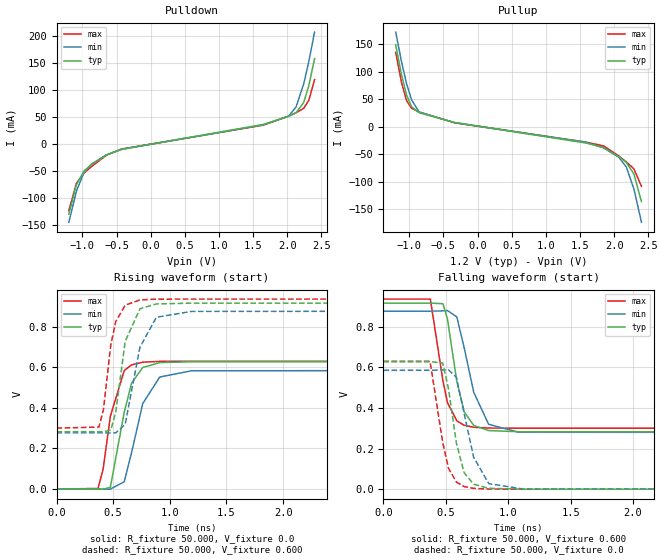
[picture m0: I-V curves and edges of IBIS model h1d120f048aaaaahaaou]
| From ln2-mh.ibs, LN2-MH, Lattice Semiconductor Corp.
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|   Model h1d120f048aaaaahaaou
[Model] h1d120f048aaaaahaaou
Model_type Output
Polarity   Non-Inverting
Enable   Active-High
Vmeas =  0.600V
Cref =  20.000pF
Rref =  50.000
Vref =  0.600V
C_comp   2.000pF   1.500pF   2.500pF
[Temperature Range]   25.000   0.125k   -40.000
[Voltage Range]   1.200V   1.160V   1.240V
[C Comp Corner]
C_comp   2.000pF   1.500pF   2.500pF
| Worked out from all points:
|   slope of the pulldown table from 0 to 0.18 V, typ, clamps not added: 44.5 ohm
|   slope of the pullup table from 0 to 0.18 V, typ, clamps not added: 44.9 ohm
|   rising waveform, R_fixture 50.000, V_fixture 0.0: 20-80 % time 122ps typ, 154ps min, 109ps max; typ from 0 V to 0.627 V
|   rising waveform, R_fixture 50.000, V_fixture 0.600: 20-80 % time 102ps typ, 129ps min, 92.1ps max; typ from 0.282 V to 0.916 V
|   falling waveform, R_fixture 50.000, V_fixture 0.600: 20-80 % time 106ps typ, 137ps min, 95.6ps max; typ from 0.916 V to 0.282 V
|   falling waveform, R_fixture 50.000, V_fixture 0.0: 20-80 % time 102ps typ, 127ps min, 94.6ps max; typ from 0.627 V to 0 V
[Pulldown]
|Voltage   I(typ)   I(min)   I(max)
-1.2V     -130.1mA   -144.7mA   -123.4mA
-1.089V   -75.5mA    -87.51mA   -72.94mA
-978mV    -50mA      -52.63mA   -53.82mA
-867mV    -38.07mA   -36.94mA   -41.6mA
-645mV    -19.68mA   -19.73mA   -20.27mA
-423mV    -9.624mA   -9.722mA   -9.051mA
1.649V    36.31mA    35.55mA    34.98mA
2.019V    51.34mA    51.54mA    51.84mA
2.13V     58.1mA     69.13mA    58.18mA
2.241V    77.15mA    111.6mA    66.35mA
2.315V    107.9mA    152.7mA    80.79mA
2.4V      158.2mA    207.4mA    119.5mA
[Pullup]
|Voltage   I(typ)   I(min)   I(max)
-1.2V     149.1mA    172.2mA    135.3mA
-1.115V   94.65mA    118.3mA    80.65mA
-1.041V   57.63mA    78.35mA    47.41mA
-967mV    36.14mA    48.7mA     33.41mA
-856mV    25.33mA    26.57mA    26.62mA
-338mV    7.596mA    7.177mA    7.095mA
1.586V    -29.78mA   -28.42mA   -28.15mA
1.845V    -38.03mA   -38.69mA   -35.06mA
2.067V    -54.56mA   -55.53mA   -53.26mA
2.178V    -65.11mA   -73.44mA   -64.22mA
2.289V    -86.23mA   -113.3mA   -76.88mA
2.4V      -136.4mA   -174mA     -108.6mA
[Ramp]
| variable   typ   min   max
dV/dt_r   0.376/0.122n   0.351/0.154n   0.378/0.109n
dV/dt_f   0.380/0.114n   0.365/0.153n   0.383/96.653p
R_load = 50.000
[Rising Waveform]
R_fixture= 50.000
V_fixture= 0.0
V_fixture_min= 0.0
V_fixture_max= 0.0
|time   V(typ)   V(min)   V(max)
0s        1.292uV    7.005uV    589.2nV
366ps     73.3uV     52.3uV     3.208mV
411ps     -441uV     74.36uV    97.21mV
475ps     8.352mV    -316.3uV   358.1mV
598ps     379.8mV    36.23mV    584.5mV
663ps     522.6mV    181.1mV    611.9mV
761ps     598.9mV    421.2mV    625.1mV
911ps     623mV      552mV      629mV
1.193ns   627.3mV    582.9mV    629.4mV
10ns      627.3mV    585.3mV    629.4mV
[Rising Waveform]
R_fixture= 50.000
V_fixture= 0.600
V_fixture_min= 0.583
V_fixture_max= 0.619
|time   V(typ)   V(min)   V(max)
0s        282.5mV    276.8mV    300.3mV
374ps     282.5mV    276.9mV    305.6mV
414ps     282.1mV    276.9mV    390.7mV
479ps     290.2mV    276.5mV    711.1mV
523ps     380.2mV    276.8mV    825.2mV
606ps     727.3mV    318.8mV    905.9mV
736ps     888mV      698.4mV    931.8mV
881ps     912mV      846.2mV    935.6mV
1.192ns   915.9mV    875.3mV    936mV
10ns      915.9mV    876.6mV    936mV
[Falling Waveform]
R_fixture= 50.000
V_fixture= 0.600
V_fixture_min= 0.583
V_fixture_max= 0.619
|time   V(typ)   V(min)   V(max)
0s        915.9mV    876.6mV    936mV
376ps     916.1mV    876.6mV    936.1mV
477ps     913.3mV    877.9mV    533.7mV
513ps     838.8mV    879.5mV    426.5mV
588ps     531mV      848.5mV    336.4mV
648ps     380.1mV    694.2mV    314.3mV
724ps     313.3mV    476.5mV    304.6mV
843ps     288.6mV    319.3mV    300.9mV
1.083ns   282.8mV    280.2mV    300.2mV
10ns      282.5mV    276.8mV    300.3mV
[Falling Waveform]
R_fixture= 50.000
V_fixture= 0.0
V_fixture_min= 0.0
V_fixture_max= 0.0
|time   V(typ)   V(min)   V(max)
0s        627.3mV    585.3mV    629.4mV
374ps     627.9mV    585.3mV    628.9mV
475ps     621.4mV    587.3mV    231mV
521ps     495.4mV    588.3mV    103.2mV
585ps     225.7mV    550.2mV    34.83mV
647ps     81.12mV    372.3mV    12.87mV
723ps     24.08mV    157.7mV    3.896mV
844ps     4.07mV     26.88mV    500.9uV
1.123ns   -8.396uV   794.5uV    -77.07uV
10ns      1.3uV      7.006uV    600.6nV
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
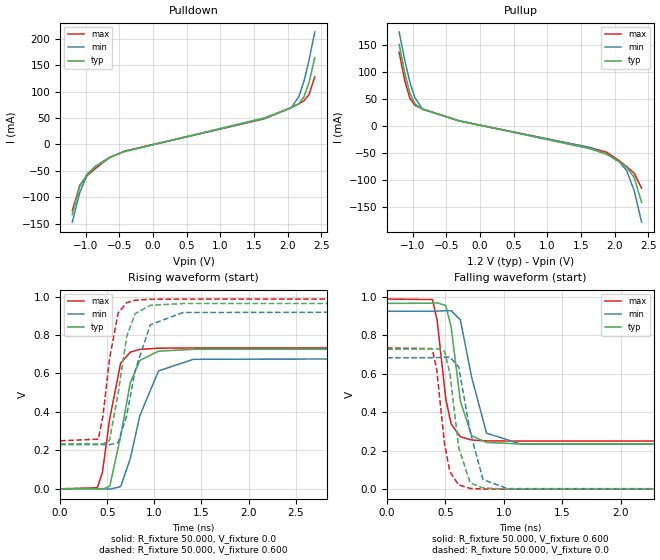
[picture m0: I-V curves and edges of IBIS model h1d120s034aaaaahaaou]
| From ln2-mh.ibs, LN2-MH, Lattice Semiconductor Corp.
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|   Model h1d120s034aaaaahaaou
[Model] h1d120s034aaaaahaaou
Model_type Output
Polarity   Non-Inverting
Enable   Active-High
Vmeas =  0.600V
Cref =  20.000pF
Rref =  50.000
Vref =  0.600V
C_comp   2.000pF   1.500pF   2.500pF
[Temperature Range]   25.000   0.125k   -40.000
[Voltage Range]   1.200V   1.160V   1.240V
[C Comp Corner]
C_comp   2.000pF   1.500pF   2.500pF
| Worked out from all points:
|   slope of the pulldown table from 0 to 0.18 V, typ, clamps not added: 31.9 ohm
|   slope of the pullup table from 0 to 0.18 V, typ, clamps not added: 32.3 ohm
|   rising waveform, R_fixture 50.000, V_fixture 0.0: 20-80 % time 162ps typ, 219ps min, 130ps max; typ from 0 V to 0.727 V
|   rising waveform, R_fixture 50.000, V_fixture 0.600: 20-80 % time 138ps typ, 184ps min, 112ps max; typ from 0.234 V to 0.965 V
|   falling waveform, R_fixture 50.000, V_fixture 0.600: 20-80 % time 96.6ps typ, 125ps min, 86ps max; typ from 0.965 V to 0.234 V
|   falling waveform, R_fixture 50.000, V_fixture 0.0: 20-80 % time 90.5ps typ, 114ps min, 82.9ps max; typ from 0.726 V to 0 V
[Pulldown]
|Voltage   I(typ)   I(min)   I(max)
-1.2V     -132.9mA   -147.4mA   -126mA
-1.089V   -79.79mA   -91.22mA   -77.41mA
-978mV    -55.54mA   -57.58mA   -59.06mA
-867mV    -43.59mA   -42.26mA   -46.67mA
-645mV    -24.61mA   -24.52mA   -24.84mA
-423mV    -13.34mA   -13.34mA   -12.58mA
1.649V    50.26mA    48.96mA    48.52mA
2.056V    69.68mA    69.95mA    70.1mA
2.167V    77.91mA    91.66mA    77.34mA
2.241V    90.47mA    120.4mA    83.09mA
2.315V    117.4mA    159.6mA    94.54mA
2.4V      164.7mA    213mA      127.8mA
[Pullup]
|Voltage   I(typ)   I(min)   I(max)
-1.2V     151mA      174.1mA    137mA
-1.115V   97.23mA    120.7mA    83.1mA
-1.041V   61.27mA    81.31mA    51.23mA
-967mV    40.99mA    52.5mA     38.23mA
-856mV    30.65mA    31.29mA    31.46mA
-301mV    9.357mA    8.783mA    8.738mA
1.623V    -42.28mA   -40.41mA   -39.95mA
1.882V    -52.67mA   -52.52mA   -49.1mA
2.067V    -66.82mA   -66.78mA   -64.74mA
2.178V    -77.1mA    -83.13mA   -75.68mA
2.289V    -95.85mA   -120.2mA   -87.97mA
2.4V      -142.4mA   -179mA     -115.9mA
[Ramp]
| variable   typ   min   max
dV/dt_r   0.436/0.162n   0.409/0.219n   0.440/0.130n
dV/dt_f   0.439/0.108n   0.421/0.144n   0.444/91.511p
R_load = 50.000
[Rising Waveform]
R_fixture= 50.000
V_fixture= 0.0
V_fixture_min= 0.0
V_fixture_max= 0.0
|time   V(typ)   V(min)   V(max)
0s        1.029uV    5.623uV    470.9nV
395ps     -219.9uV   61.53uV    5.311mV
449ps     -1.936mV   -194.2nV   85.85mV
527ps     13.2mV     -1.62mV    366.4mV
642ps     273mV      11mV       652.5mV
744ps     550.2mV    156mV      710.8mV
846ps     667.9mV    380.6mV    725.2mV
1.045ns   715.8mV    613.4mV    731.3mV
1.416ns   725.5mV    673.6mV    732.6mV
10ns      726.5mV    682.1mV    732.6mV
[Rising Waveform]
R_fixture= 50.000
V_fixture= 0.600
V_fixture_min= 0.583
V_fixture_max= 0.619
|time   V(typ)   V(min)   V(max)
0s        233.9mV    229.5mV    249.7mV
405ps     233.5mV    229.6mV    258mV
455ps     232.9mV    229.4mV    379.6mV
523ps     250.7mV    228.9mV    672.5mV
615ps     493.3mV    240.1mV    913.8mV
706ps     791.3mV    380.2mV    967.8mV
796ps     911.1mV    614.8mV    980.7mV
956ps     954.4mV    852.9mV    985.6mV
1.305ns   963.7mV    917mV      986.8mV
10ns      964.5mV    923.8mV    986.9mV
[Falling Waveform]
R_fixture= 50.000
V_fixture= 0.600
V_fixture_min= 0.583
V_fixture_max= 0.619
|time   V(typ)   V(min)   V(max)
0s        964.5mV    923.8mV    986.9mV
389ps     965.4mV    924mV      984.2mV
429ps     967.5mV    924.3mV    877.5mV
503ps     953.5mV    926.6mV    469.4mV
549ps     843.5mV    926.6mV    338.1mV
628ps     457.2mV    878.6mV    272.1mV
725ps     277mV      580.4mV    254.9mV
852ps     242.5mV    291.1mV    250.7mV
1.142ns   234.7mV    234.5mV    249.7mV
10ns      233.9mV    229.5mV    249.7mV
[Falling Waveform]
R_fixture= 50.000
V_fixture= 0.0
V_fixture_min= 0.0
V_fixture_max= 0.0
|time   V(typ)   V(min)   V(max)
0s        726.5mV    682.1mV    732.6mV
386ps     728mV      682.3mV    729.7mV
425ps     730.2mV    682.9mV    622.5mV
493ps     716.1mV    685.7mV    232.3mV
539ps     600.5mV    685.1mV    89.24mV
614ps     214mV      633.9mV    21.74mV
712ps     33.18mV    298.2mV    4.06mV
822ps     5.999mV    49.63mV    626.6uV
1.032ns   358.6uV    3.034mV    -31.47uV
10ns      1.036uV    5.62uV     481.1nV
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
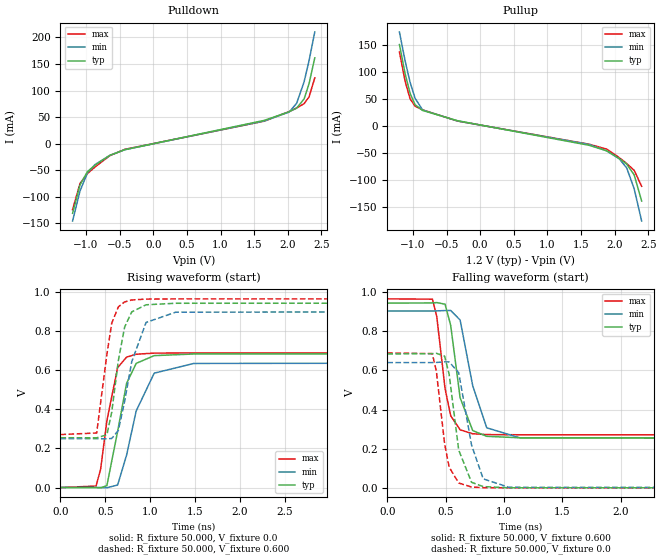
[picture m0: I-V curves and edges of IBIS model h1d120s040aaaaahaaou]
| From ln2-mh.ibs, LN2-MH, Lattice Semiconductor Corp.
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|   Model h1d120s040aaaaahaaou
[Model] h1d120s040aaaaahaaou
Model_type Output
Polarity   Non-Inverting
Enable   Active-High
Vmeas =  0.600V
Cref =  20.000pF
Rref =  50.000
Vref =  0.600V
C_comp   2.000pF   1.500pF   2.500pF
[Temperature Range]   25.000   0.125k   -40.000
[Voltage Range]   1.200V   1.160V   1.240V
[C Comp Corner]
C_comp   2.000pF   1.500pF   2.500pF
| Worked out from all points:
|   slope of the pulldown table from 0 to 0.18 V, typ, clamps not added: 36.9 ohm
|   slope of the pullup table from 0 to 0.18 V, typ, clamps not added: 37.3 ohm
|   rising waveform, R_fixture 50.000, V_fixture 0.0: 20-80 % time 158ps typ, 212ps min, 130ps max; typ from 0 V to 0.684 V
|   rising waveform, R_fixture 50.000, V_fixture 0.600: 20-80 % time 133ps typ, 177ps min, 110ps max; typ from 0.255 V to 0.943 V
|   falling waveform, R_fixture 50.000, V_fixture 0.600: 20-80 % time 98.9ps typ, 128ps min, 88.9ps max; typ from 0.943 V to 0.255 V
|   falling waveform, R_fixture 50.000, V_fixture 0.0: 20-80 % time 93.1ps typ, 116ps min, 86.7ps max; typ from 0.684 V to 0 V
[Pulldown]
|Voltage   I(typ)   I(min)   I(max)
-1.2V     -131.6mA   -146.1mA   -124.7mA
-1.089V   -77.73mA   -89.44mA   -75.31mA
-978mV    -52.9mA    -55.22mA   -56.61mA
-867mV    -40.96mA   -39.73mA   -44.3mA
-645mV    -22.27mA   -22.24mA   -22.7mA
-423mV    -11.57mA   -11.62mA   -10.93mA
1.649V    43.64mA    42.58mA    42.18mA
2.019V    59.89mA    59.32mA    60.3mA
2.13V     66.73mA    75.74mA    67.04mA
2.241V    84.04mA    116.1mA    75.18mA
2.315V    112.8mA    156.3mA    87.92mA
2.4V      161.6mA    210.3mA    123.8mA
[Pullup]
|Voltage   I(typ)   I(min)   I(max)
-1.2V     150mA      173.2mA    136.2mA
-1.115V   95.98mA    119.5mA    81.92mA
-1.041V   59.5mA     79.86mA    49.41mA
-967mV    38.64mA    50.65mA    35.94mA
-856mV    28.09mA    28.99mA    29.17mA
-338mV    9.116mA    8.575mA    8.54mA
1.623V    -36.49mA   -34.96mA   -34.51mA
1.882V    -46.66mA   -46.87mA   -43.48mA
2.067V    -60.85mA   -61.26mA   -59.2mA
2.178V    -71.25mA   -78.35mA   -70.16mA
2.289V    -91.11mA   -116.8mA   -82.62mA
2.4V      -139.5mA   -176.5mA   -112.3mA
[Ramp]
| variable   typ   min   max
dV/dt_r   0.410/0.159n   0.384/0.212n   0.413/0.130n
dV/dt_f   0.414/0.110n   0.397/0.149n   0.418/93.884p
R_load = 50.000
[Rising Waveform]
R_fixture= 50.000
V_fixture= 0.0
V_fixture_min= 0.0
V_fixture_max= 0.0
|time   V(typ)   V(min)   V(max)
0s        1.143uV    6.223uV    521.7nV
397ps     -246.2uV   65.82uV    7.352mV
448ps     -1.707mV   9.459uV    93.32mV
518ps     9.667mV    -1.152mV   341.7mV
638ps     287.9mV    12.74mV    613.5mV
738ps     533.2mV    166.5mV    667.2mV
845ps     635.2mV    391.9mV    681.9mV
1.046ns   674.8mV    585.1mV    687.6mV
1.486ns   683.1mV    634.7mV    688.7mV
10ns      683.6mV    639.6mV    688.7mV
[Rising Waveform]
R_fixture= 50.000
V_fixture= 0.600
V_fixture_min= 0.583
V_fixture_max= 0.619
|time   V(typ)   V(min)   V(max)
0s        254.7mV    249.8mV    271mV
404ps     254.4mV    249.9mV    279mV
518ps     269.4mV    249.3mV    680.7mV
572ps     385.2mV    250.9mV    840.3mV
646ps     649.9mV    292.3mV    924.3mV
716ps     821mV      440.7mV    949.7mV
795ps     898.5mV    643.1mV    959.4mV
955ps     934.9mV    844.5mV    964.1mV
1.285ns   942.7mV    897mV      965.1mV
10ns      943.4mV    903.1mV    965.2mV
[Falling Waveform]
R_fixture= 50.000
V_fixture= 0.600
V_fixture_min= 0.583
V_fixture_max= 0.619
|time   V(typ)   V(min)   V(max)
0s        943.4mV    903.1mV    965.1mV
387ps     944.3mV    903.2mV    963.6mV
424ps     946.1mV    903.5mV    874.3mV
495ps     937.9mV    905.5mV    507mV
543ps     830.4mV    905.9mV    368.3mV
624ps     460.4mV    857.2mV    296.3mV
732ps     292.4mV    521.6mV    276.2mV
852ps     263.1mV    306.6mV    272mV
1.142ns   255.4mV    254.4mV    271mV
10ns      254.7mV    249.8mV    271mV
[Falling Waveform]
R_fixture= 50.000
V_fixture= 0.0
V_fixture_min= 0.0
V_fixture_max= 0.0
|time   V(typ)   V(min)   V(max)
0s        683.6mV    639.6mV    688.7mV
385ps     685.2mV    639.8mV    685.6mV
420ps     687.2mV    640.4mV    597mV
491ps     672.8mV    643.3mV    225mV
530ps     579.8mV    643.1mV    105.7mV
612ps     192.9mV    588mV      24.59mV
722ps     28.36mV    218.3mV    4.08mV
822ps     6.46mV     45.82mV    773.7uV
1.042ns   300uV      2.813mV    -60.66uV
10ns      1.151uV    6.222uV    532.5nV
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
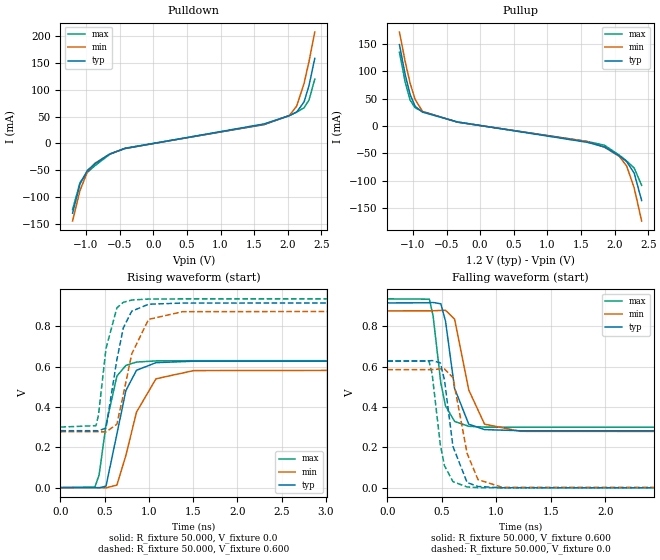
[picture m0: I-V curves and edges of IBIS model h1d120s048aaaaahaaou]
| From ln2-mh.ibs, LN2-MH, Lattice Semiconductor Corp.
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|   Model h1d120s048aaaaahaaou
[Model] h1d120s048aaaaahaaou
Model_type Output
Polarity   Non-Inverting
Enable   Active-High
Vmeas =  0.600V
Cref =  20.000pF
Rref =  50.000
Vref =  0.600V
C_comp   2.000pF   1.500pF   2.500pF
[Temperature Range]   25.000   0.125k   -40.000
[Voltage Range]   1.200V   1.160V   1.240V
[C Comp Corner]
C_comp   2.000pF   1.500pF   2.500pF
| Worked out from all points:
|   slope of the pulldown table from 0 to 0.18 V, typ, clamps not added: 44.5 ohm
|   slope of the pullup table from 0 to 0.18 V, typ, clamps not added: 44.9 ohm
|   rising waveform, R_fixture 50.000, V_fixture 0.0: 20-80 % time 169ps typ, 226ps min, 138ps max; typ from 0 V to 0.627 V
|   rising waveform, R_fixture 50.000, V_fixture 0.600: 20-80 % time 143ps typ, 192ps min, 116ps max; typ from 0.282 V to 0.916 V
|   falling waveform, R_fixture 50.000, V_fixture 0.600: 20-80 % time 107ps typ, 140ps min, 93.7ps max; typ from 0.916 V to 0.282 V
|   falling waveform, R_fixture 50.000, V_fixture 0.0: 20-80 % time 99.6ps typ, 124ps min, 91.7ps max; typ from 0.627 V to 0 V
[Pulldown]
|Voltage   I(typ)   I(min)   I(max)
-1.2V     -130.1mA   -144.7mA   -123.4mA
-1.089V   -75.5mA    -87.51mA   -72.94mA
-978mV    -50mA      -52.63mA   -53.82mA
-867mV    -38.07mA   -36.94mA   -41.6mA
-645mV    -19.68mA   -19.73mA   -20.27mA
-423mV    -9.624mA   -9.722mA   -9.051mA
1.649V    36.31mA    35.55mA    34.98mA
2.019V    51.34mA    51.54mA    51.84mA
2.13V     58.1mA     69.13mA    58.18mA
2.241V    77.15mA    111.6mA    66.35mA
2.315V    107.9mA    152.7mA    80.79mA
2.4V      158.2mA    207.4mA    119.5mA
[Pullup]
|Voltage   I(typ)   I(min)   I(max)
-1.2V     149.1mA    172.2mA    135.3mA
-1.115V   94.65mA    118.3mA    80.64mA
-1.041V   57.63mA    78.35mA    47.41mA
-967mV    36.14mA    48.7mA     33.41mA
-856mV    25.33mA    26.57mA    26.62mA
-338mV    7.596mA    7.177mA    7.095mA
1.586V    -29.78mA   -28.42mA   -28.15mA
1.845V    -38.03mA   -38.69mA   -35.06mA
2.067V    -54.56mA   -55.53mA   -53.26mA
2.178V    -65.11mA   -73.44mA   -64.22mA
2.289V    -86.23mA   -113.3mA   -76.88mA
2.4V      -136.4mA   -174mA     -108.6mA
[Ramp]
| variable   typ   min   max
dV/dt_r   0.376/0.169n   0.351/0.226n   0.378/0.138n
dV/dt_f   0.380/0.120n   0.365/0.166n   0.383/97.813p
R_load = 50.000
[Rising Waveform]
R_fixture= 50.000
V_fixture= 0.0
V_fixture_min= 0.0
V_fixture_max= 0.0
|time   V(typ)   V(min)   V(max)
0s        1.292uV    7.005uV    589.2nV
390ps     -108.8uV   65.23uV    3.143mV
437ps     -1.173mV   71.07uV    62.94mV
515ps     7.271mV    -1.097mV   310.2mV
638ps     265.6mV    12.33mV    552.9mV
740ps     481.7mV    160.1mV    606.3mV
860ps     582.1mV    374.6mV    622.7mV
1.08ns    619.6mV    539.6mV    628.4mV
1.506ns   626.8mV    580.3mV    629.4mV
10ns      627.3mV    585.3mV    629.4mV
[Rising Waveform]
R_fixture= 50.000
V_fixture= 0.600
V_fixture_min= 0.583
V_fixture_max= 0.619
|time   V(typ)   V(min)   V(max)
0s        282.5mV    276.8mV    300.3mV
402ps     282.2mV    276.9mV    307.1mV
430ps     281.9mV    276.9mV    359.9mV
515ps     295.2mV    276.4mV    689.9mV
638ps     634.9mV    314.2mV    891.3mV
710ps     790.9mV    460mV      918.6mV
806ps     875mV      663.1mV    930.4mV
996ps     909.3mV    834.3mV    935.2mV
1.381ns   915.4mV    872.5mV    935.9mV
10ns      915.9mV    876.6mV    936mV
[Falling Waveform]
R_fixture= 50.000
V_fixture= 0.600
V_fixture_min= 0.583
V_fixture_max= 0.619
|time   V(typ)   V(min)   V(max)
0s        915.9mV    876.6mV    936mV
386ps     916.6mV    876.7mV    934.6mV
420ps     918.3mV    876.9mV    850.9mV
491ps     911.6mV    878.8mV    518.3mV
534ps     825mV      879.4mV    405.9mV
617ps     492.5mV    835.5mV    329.1mV
747ps     315.1mV    484.5mV    304.8mV
892ps     288.5mV    315.2mV    300.8mV
1.222ns   282.8mV    279.8mV    300.2mV
10ns      282.5mV    276.8mV    300.3mV
[Falling Waveform]
R_fixture= 50.000
V_fixture= 0.0
V_fixture_min= 0.0
V_fixture_max= 0.0
|time   V(typ)   V(min)   V(max)
0s        627.3mV    585.3mV    629.4mV
382ps     628.7mV    585.4mV    628mV
411ps     630.4mV    585.8mV    564.7mV
486ps     619.3mV    588.7mV    214.3mV
524ps     535.1mV    589mV      110.1mV
602ps     205mV      545.6mV    30.66mV
732ps     26.2mV     170.4mV    4.269mV
832ps     6.647mV    40.49mV    884.1uV
1.052ns   319.6uV    2.984mV    -87.66uV
10ns      1.301uV    7.007uV    599.8nV
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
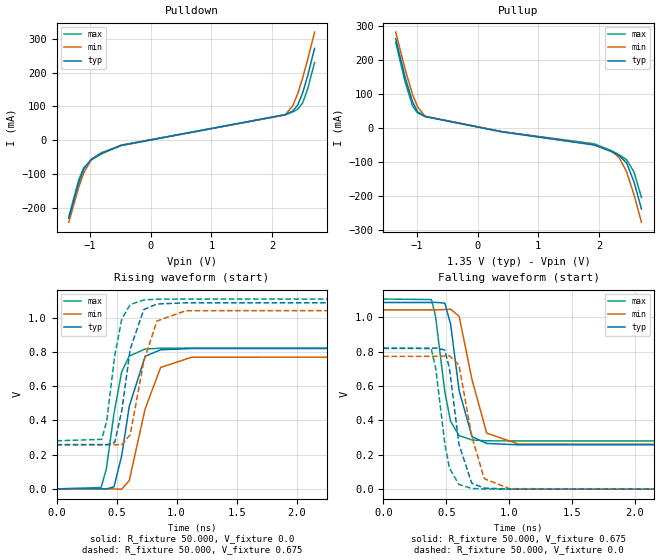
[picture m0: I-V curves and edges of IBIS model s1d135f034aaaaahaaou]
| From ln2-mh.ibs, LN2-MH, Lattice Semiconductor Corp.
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|   Model s1d135f034aaaaahaaou
[Model] s1d135f034aaaaahaaou
Model_type Output
Polarity   Non-Inverting
Enable   Active-High
Vmeas =  0.675V
Cref =  30.000pF
Rref =  50.000
Vref =  0.675V
C_comp   2.000pF   1.500pF   2.500pF
[Temperature Range]   25.000   0.125k   -40.000
[Voltage Range]   1.350V   1.310V   1.390V
[C Comp Corner]
C_comp   2.000pF   1.500pF   2.500pF
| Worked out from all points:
|   slope of the pulldown table from 0 to 0.203 V, typ, clamps not added: 30.8 ohm
|   slope of the pullup table from 0 to 0.203 V, typ, clamps not added: 31.9 ohm
|   rising waveform, R_fixture 50.000, V_fixture 0.0: 20-80 % time 121ps typ, 146ps min, 107ps max; typ from 0 V to 0.82 V
|   rising waveform, R_fixture 50.000, V_fixture 0.675: 20-80 % time 107ps typ, 126ps min, 97.6ps max; typ from 0.258 V to 1.09 V
|   falling waveform, R_fixture 50.000, V_fixture 0.675: 20-80 % time 94.7ps typ, 123ps min, 89.5ps max; typ from 1.09 V to 0.258 V
|   falling waveform, R_fixture 50.000, V_fixture 0.0: 20-80 % time 90.1ps typ, 114ps min, 87ps max; typ from 0.82 V to 0 V
[Pulldown]
|Voltage   I(typ)   I(min)   I(max)
-1.35V    -232.1mA   -243.5mA   -226.7mA
-1.186V   -125.3mA   -139.4mA   -118mA
-1.104V   -85.87mA   -97.7mA    -81.8mA
-981mV    -56.74mA   -58.23mA   -59.49mA
-817mV    -39.68mA   -37.64mA   -41.41mA
-489mV    -16.31mA   -15.97mA   -14.94mA
2.217V    75.77mA    74.45mA    74.87mA
2.34V     86.1mA     101.7mA    83.47mA
2.422V    103.9mA    137.5mA    91.32mA
2.504V    140.3mA    184.6mA    110.4mA
2.586V    190.7mA    238.7mA    151.7mA
2.7V      271.8mA    320.2mA    229.8mA
[Pullup]
|Voltage   I(typ)   I(min)   I(max)
-1.35V    261.8mA    281.1mA    251mA
-1.195V   148.5mA    171.6mA    134.6mA
-1.072V   75.86mA    97.64mA    63.85mA
-990mV    47.26mA    61.36mA    43mA
-867mV    32.53mA    33.87mA    33.01mA
404mV     -12.56mA   -11.72mA   -11.74mA
1.921V    -50.98mA   -50.33mA   -47.39mA
2.208V    -70.34mA   -69.95mA   -67.85mA
2.331V    -81.62mA   -87.27mA   -79.96mA
2.454V    -103.5mA   -129.4mA   -93.9mA
2.577V    -159.7mA   -197.1mA   -130.6mA
2.7V      -239.3mA   -278mA     -205.3mA
[Ramp]
| variable   typ   min   max
dV/dt_r   0.492/0.121n   0.464/0.147n   0.493/0.108n
dV/dt_f   0.500/0.104n   0.476/0.138n   0.497/93.467p
R_load = 50.000
[Rising Waveform]
R_fixture= 50.000
V_fixture= 0.0
V_fixture_min= 0.0
V_fixture_max= 0.0
|time   V(typ)   V(min)   V(max)
0s        1.101uV    6.191uV    508.8nV
371ps     55.86uV    43.11uV    7.869mV
415ps     -592.1uV   70.24uV    116.8mV
479ps     12.27mV    -410uV     442mV
543ps     193.8mV    -1.777mV   683.8mV
606ps     482.5mV    48.7mV     775.4mV
738ps     773.8mV    466.5mV    816.2mV
867ps     811.8mV    708.7mV    821.1mV
1.126ns   819.2mV    768.3mV    821.8mV
10ns      819.5mV    773.1mV    821.8mV
[Rising Waveform]
R_fixture= 50.000
V_fixture= 0.675
V_fixture_min= 0.656
V_fixture_max= 0.696
|time   V(typ)   V(min)   V(max)
0s        257.6mV    258.3mV    280.7mV
376ps     257.6mV    258.4mV    288.8mV
418ps     257.1mV    258.4mV    394.9mV
485ps     271.7mV    257.9mV    779mV
544ps     457.5mV    258mV      992.5mV
614ps     816.5mV    316.7mV    1.076V
727ps     1.047V     744.7mV    1.103V
836ps     1.079V     979.8mV    1.107V
1.076ns   1.086V     1.04V      1.108V
10ns      1.087V     1.044V     1.107V
[Falling Waveform]
R_fixture= 50.000
V_fixture= 0.675
V_fixture_min= 0.656
V_fixture_max= 0.696
|time   V(typ)   V(min)   V(max)
0s        1.087V     1.044V     1.107V
382ps     1.087V     1.044V     1.104V
414ps     1.088V     1.044V     1.008V
488ps     1.083V     1.046V     566.8mV
534ps     960.3mV    1.048V     394.3mV
602ps     572.6mV    1.006V     311.8mV
704ps     305.5mV    637.5mV    286.3mV
821ps     266mV      326.1mV    281.7mV
1.074ns   258.2mV    262.4mV    280.8mV
10ns      257.6mV    258.3mV    280.7mV
[Falling Waveform]
R_fixture= 50.000
V_fixture= 0.0
V_fixture_min= 0.0
V_fixture_max= 0.0
|time   V(typ)   V(min)   V(max)
0s        819.5mV    773.1mV    821.8mV
380ps     820.1mV    773.2mV    819.3mV
416ps     822mV      773.4mV    702.5mV
488ps     810mV      775.6mV    264mV
525ps     702.6mV    776.6mV    122.5mV
600ps     261.8mV    722.7mV    27.14mV
702ps     34.71mV    309.5mV    4.16mV
801ps     6.249mV    61.23mV    654.2uV
1.001ns   290.7uV    2.81mV     -41.59uV
10ns      1.108uV    6.188uV    519.3nV
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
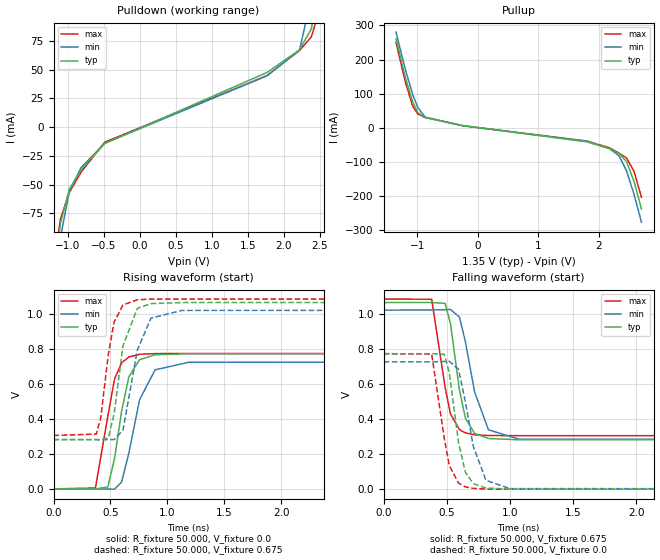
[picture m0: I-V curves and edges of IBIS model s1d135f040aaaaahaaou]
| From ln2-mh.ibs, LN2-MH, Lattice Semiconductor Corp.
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|   Model s1d135f040aaaaahaaou
[Model] s1d135f040aaaaahaaou
Model_type Output
Polarity   Non-Inverting
Enable   Active-High
Vmeas =  0.675V
Cref =  30.000pF
Rref =  50.000
Vref =  0.675V
C_comp   2.000pF   1.500pF   2.500pF
[Temperature Range]   25.000   0.125k   -40.000
[Voltage Range]   1.350V   1.310V   1.390V
[C Comp Corner]
C_comp   2.000pF   1.500pF   2.500pF
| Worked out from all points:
|   slope of the pulldown table from 0 to 0.203 V, typ, clamps not added: 35.6 ohm
|   slope of the pullup table from 0 to 0.203 V, typ, clamps not added: 36.9 ohm
|   rising waveform, R_fixture 50.000, V_fixture 0.0: 20-80 % time 120ps typ, 148ps min, 109ps max; typ from 0 V to 0.771 V
|   rising waveform, R_fixture 50.000, V_fixture 0.675: 20-80 % time 103ps typ, 125ps min, 96.7ps max; typ from 0.281 V to 1.06 V
|   falling waveform, R_fixture 50.000, V_fixture 0.675: 20-80 % time 97.7ps typ, 126ps min, 92.9ps max; typ from 1.06 V to 0.281 V
|   falling waveform, R_fixture 50.000, V_fixture 0.0: 20-80 % time 93.7ps typ, 118ps min, 91.1ps max; typ from 0.771 V to 0 V
[Pulldown]
|Voltage   I(typ)   I(min)   I(max)
-1.35V    -231.1mA   -242.5mA   -225.9mA
-1.186V   -123.8mA   -138.1mA   -116.7mA
-1.104V   -83.85mA   -96mA      -79.82mA
-981mV    -54mA      -55.88mA   -57.04mA
-817mV    -37mA      -35.13mA   -39.09mA
-489mV    -14.24mA   -14.03mA   -13.08mA
1.766V    47.58mA    44.68mA    44.9mA
2.217V    67.27mA    67.18mA    66.71mA
2.381V    85.6mA     113.1mA    78.52mA
2.504V    136mA      181.4mA    104.5mA
2.586V    187.6mA    236.1mA    148.1mA
2.7V      269.4mA    318mA      227.5mA
[Pullup]
|Voltage   I(typ)   I(min)   I(max)
-1.35V    261mA      280.3mA    250.5mA
-1.195V   147.5mA    170.6mA    133.8mA
-1.072V   74.23mA    96.25mA    62.23mA
-990mV    44.94mA    59.52mA    40.71mA
-867mV    29.86mA    31.47mA    30.65mA
-252mV    6.942mA    6.538mA    6.422mA
1.798V    -40.81mA   -39.31mA   -38.52mA
2.167V    -60.38mA   -60.19mA   -57.95mA
2.331V    -75.2mA    -82mA      -73.9mA
2.454V    -98.52mA   -125.8mA   -88.11mA
2.577V    -156.7mA   -194.5mA   -127.1mA
2.7V      -237.1mA   -275.9mA   -203.1mA
[Ramp]
| variable   typ   min   max
dV/dt_r   0.463/0.120n   0.435/0.148n   0.464/0.109n
dV/dt_f   0.472/0.107n   0.448/0.143n   0.469/96.098p
R_load = 50.000
[Rising Waveform]
R_fixture= 50.000
V_fixture= 0.0
V_fixture_min= 0.0
V_fixture_max= 0.0
|time   V(typ)   V(min)   V(max)
0s        1.224uV    6.848uV    563.4nV
368ps     64.49uV    46.62uV    5.204mV
477ps     10.97mV    -352.9uV   414.8mV
536ps     173.6mV    -1.452mV   627.4mV
598ps     443.8mV    39.28mV    719mV
662ps     639.9mV    205.8mV    752.8mV
756ps     737.1mV    508.8mV    767.8mV
892ps     765.5mV    679.3mV    771.9mV
1.186ns   771.1mV    722.3mV    772.5mV
10ns      771.2mV    725.1mV    772.5mV
[Rising Waveform]
R_fixture= 50.000
V_fixture= 0.675
V_fixture_min= 0.656
V_fixture_max= 0.696
|time   V(typ)   V(min)   V(max)
0s        280.9mV    281.2mV    304.7mV
376ps     280.9mV    281.2mV    312.8mV
415ps     280.4mV    281.2mV    406mV
481ps     291.6mV    280.8mV    765.4mV
532ps     426.7mV    281.2mV    951.6mV
610ps     815.9mV    334.7mV    1.049V
736ps     1.03V      791.7mV    1.079V
856ps     1.057V     974.1mV    1.083V
1.125ns   1.063V     1.018V     1.083V
10ns      1.063V     1.021V     1.083V
[Falling Waveform]
R_fixture= 50.000
V_fixture= 0.675
V_fixture_min= 0.656
V_fixture_max= 0.696
|time   V(typ)   V(min)   V(max)
0s        1.063V     1.02V      1.083V
380ps     1.063V     1.021V     1.082V
486ps     1.059V     1.022V     582.9mV
529ps     943.9mV    1.024V     428.3mV
600ps     565.6mV    980.4mV    339.4mV
647ps     405.7mV    841mV      320.5mV
720ps     317.8mV    554.1mV    309.6mV
830ps     288.5mV    338.3mV    305.6mV
1.07ns    281.3mV    285.3mV    304.7mV
10ns      280.9mV    281.2mV    304.7mV
[Falling Waveform]
R_fixture= 50.000
V_fixture= 0.0
V_fixture_min= 0.0
V_fixture_max= 0.0
|time   V(typ)   V(min)   V(max)
0s        771.2mV    725.1mV    772.5mV
380ps     771.8mV    725.2mV    769.1mV
480ps     767.7mV    727.2mV    289.5mV
520ps     662.7mV    728.4mV    134mV
593ps     263.7mV    683mV      34.32mV
647ps     96.77mV    498.6mV    13.26mV
710ps     31.16mV    244mV      4.463mV
810ps     6.145mV    50.3mV     719.5uV
1ns       290.1uV    3.202mV    -67.47uV
10ns      1.231uV    6.847uV    574.8nV
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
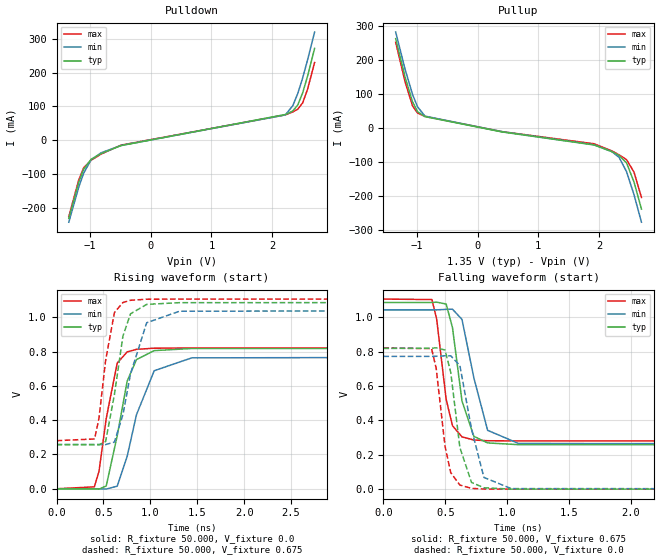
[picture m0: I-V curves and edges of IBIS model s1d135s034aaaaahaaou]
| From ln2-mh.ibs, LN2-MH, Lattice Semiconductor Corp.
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|   Model s1d135s034aaaaahaaou
[Model] s1d135s034aaaaahaaou
Model_type Output
Polarity   Non-Inverting
Enable   Active-High
Vmeas =  0.675V
Cref =  30.000pF
Rref =  50.000
Vref =  0.675V
C_comp   2.000pF   1.500pF   2.500pF
[Temperature Range]   25.000   0.125k   -40.000
[Voltage Range]   1.350V   1.310V   1.390V
[C Comp Corner]
C_comp   2.000pF   1.500pF   2.500pF
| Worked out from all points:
|   slope of the pulldown table from 0 to 0.203 V, typ, clamps not added: 30.8 ohm
|   slope of the pullup table from 0 to 0.203 V, typ, clamps not added: 31.9 ohm
|   rising waveform, R_fixture 50.000, V_fixture 0.0: 20-80 % time 164ps typ, 222ps min, 131ps max; typ from 0 V to 0.82 V
|   rising waveform, R_fixture 50.000, V_fixture 0.675: 20-80 % time 137ps typ, 183ps min, 112ps max; typ from 0.258 V to 1.09 V
|   falling waveform, R_fixture 50.000, V_fixture 0.675: 20-80 % time 96.6ps typ, 125ps min, 86.6ps max; typ from 1.09 V to 0.258 V
|   falling waveform, R_fixture 50.000, V_fixture 0.0: 20-80 % time 88.6ps typ, 112ps min, 83.4ps max; typ from 0.82 V to 0 V
[Pulldown]
|Voltage   I(typ)   I(min)   I(max)
-1.35V    -232.1mA   -243.5mA   -226.7mA
-1.186V   -125.3mA   -139.4mA   -118mA
-1.104V   -85.87mA   -97.7mA    -81.8mA
-981mV    -56.74mA   -58.23mA   -59.49mA
-817mV    -39.68mA   -37.64mA   -41.41mA
-489mV    -16.31mA   -15.97mA   -14.94mA
2.217V    75.77mA    74.45mA    74.87mA
2.34V     86.1mA     101.7mA    83.47mA
2.422V    103.9mA    137.5mA    91.32mA
2.504V    140.3mA    184.6mA    110.4mA
2.586V    190.7mA    238.7mA    151.7mA
2.7V      271.8mA    320.2mA    229.8mA
[Pullup]
|Voltage   I(typ)   I(min)   I(max)
-1.35V    261.8mA    281.1mA    251mA
-1.195V   148.5mA    171.6mA    134.6mA
-1.072V   75.86mA    97.64mA    63.85mA
-990mV    47.26mA    61.36mA    43mA
-867mV    32.53mA    33.87mA    33.01mA
404mV     -12.56mA   -11.72mA   -11.74mA
1.921V    -50.98mA   -50.33mA   -47.39mA
2.208V    -70.34mA   -69.94mA   -67.85mA
2.331V    -81.62mA   -87.27mA   -79.96mA
2.454V    -103.5mA   -129.4mA   -93.9mA
2.577V    -159.7mA   -197.1mA   -130.6mA
2.7V      -239.3mA   -278mA     -205.3mA
[Ramp]
| variable   typ   min   max
dV/dt_r   0.492/0.165n   0.464/0.222n   0.493/0.131n
dV/dt_f   0.500/0.110n   0.476/0.148n   0.497/92.982p
R_load = 50.000
[Rising Waveform]
R_fixture= 50.000
V_fixture= 0.0
V_fixture_min= 0.0
V_fixture_max= 0.0
|time   V(typ)   V(min)   V(max)
0s        1.101uV    6.191uV    508.8nV
403ps     -413.5uV   70.36uV    11.13mV
453ps     -2.374mV   -37.66uV   102.3mV
530ps     16.5mV     -1.762mV   410.9mV
647ps     309.5mV    15.12mV    733.3mV
753ps     627.9mV    189mV      798.6mV
852ps     753.7mV    431.5mV    813.5mV
1.041ns   806.2mV    688.8mV    820.2mV
1.441ns   818.4mV    763.8mV    821.7mV
10ns      819.5mV    773.1mV    821.8mV
[Rising Waveform]
R_fixture= 50.000
V_fixture= 0.675
V_fixture_min= 0.656
V_fixture_max= 0.696
|time   V(typ)   V(min)   V(max)
0s        257.6mV    258.3mV    280.7mV
406ps     257.1mV    258.4mV    290.5mV
453ps     256.6mV    258.2mV    414.2mV
523ps     275.4mV    257.8mV    747.6mV
617ps     549.3mV    272.5mV    1.028V
708ps     891.4mV    433mV      1.087V
789ps     1.021V     670.7mV    1.1V
961ps     1.076V     968.9mV    1.106V
1.311ns   1.086V     1.036V     1.107V
10ns      1.087V     1.044V     1.107V
[Falling Waveform]
R_fixture= 50.000
V_fixture= 0.675
V_fixture_min= 0.656
V_fixture_max= 0.696
|time   V(typ)   V(min)   V(max)
0s        1.087V     1.044V     1.107V
392ps     1.087V     1.044V     1.104V
430ps     1.089V     1.044V     992.3mV
507ps     1.078V     1.047V     523.3mV
558ps     941.2mV    1.048V     369.7mV
635ps     513.1mV    988.4mV    304.3mV
731ps     307.4mV    647.4mV    286.2mV
842ps     269.3mV    342.5mV    282mV
1.092ns   259mV      266.1mV    280.8mV
10ns      257.6mV    258.3mV    280.7mV
[Falling Waveform]
R_fixture= 50.000
V_fixture= 0.0
V_fixture_min= 0.0
V_fixture_max= 0.0
|time   V(typ)   V(min)   V(max)
0s        819.5mV    773.1mV    821.8mV
389ps     820.9mV    773.3mV    818.6mV
426ps     823mV      773.8mV    706.1mV
498ps     810.2mV    776.6mV    249.5mV
544ps     680mV      776.5mV    95.87mV
618ps     241.4mV    719.8mV    23.76mV
712ps     38.97mV    349mV      4.576mV
812ps     7.945mV    68.27mV    721.7uV
1.032ns   337uV      3.346mV    -59.97uV
10ns      1.108uV    6.188uV    520.1nV
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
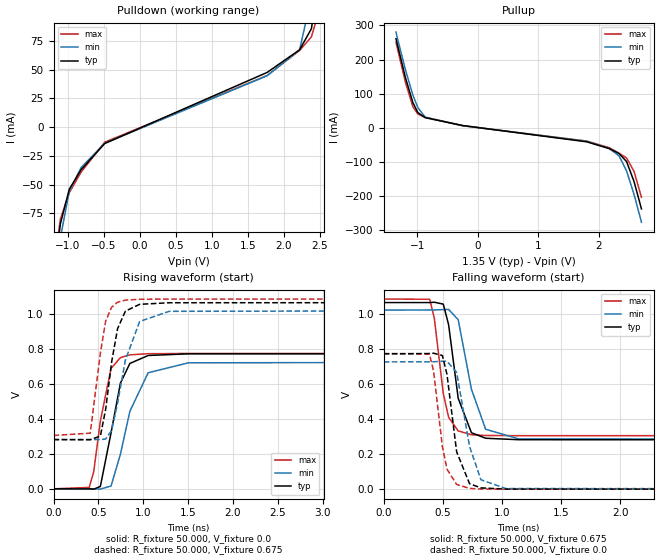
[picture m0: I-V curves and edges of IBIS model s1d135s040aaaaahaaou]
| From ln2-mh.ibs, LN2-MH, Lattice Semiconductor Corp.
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|   Model s1d135s040aaaaahaaou
[Model] s1d135s040aaaaahaaou
Model_type Output
Polarity   Non-Inverting
Enable   Active-High
Vmeas =  0.675V
Cref =  30.000pF
Rref =  50.000
Vref =  0.675V
C_comp   2.000pF   1.500pF   2.500pF
[Temperature Range]   25.000   0.125k   -40.000
[Voltage Range]   1.350V   1.310V   1.390V
[C Comp Corner]
C_comp   2.000pF   1.500pF   2.500pF
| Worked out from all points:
|   slope of the pulldown table from 0 to 0.203 V, typ, clamps not added: 35.6 ohm
|   slope of the pullup table from 0 to 0.203 V, typ, clamps not added: 36.9 ohm
|   rising waveform, R_fixture 50.000, V_fixture 0.0: 20-80 % time 161ps typ, 217ps min, 132ps max; typ from 0 V to 0.771 V
|   rising waveform, R_fixture 50.000, V_fixture 0.675: 20-80 % time 134ps typ, 180ps min, 111ps max; typ from 0.281 V to 1.06 V
|   falling waveform, R_fixture 50.000, V_fixture 0.675: 20-80 % time 98.5ps typ, 128ps min, 89.7ps max; typ from 1.06 V to 0.281 V
|   falling waveform, R_fixture 50.000, V_fixture 0.0: 20-80 % time 91.5ps typ, 115ps min, 87.4ps max; typ from 0.771 V to 0 V
[Pulldown]
|Voltage   I(typ)   I(min)   I(max)
-1.35V    -231.1mA   -242.5mA   -225.9mA
-1.186V   -123.8mA   -138.1mA   -116.7mA
-1.104V   -83.85mA   -96mA      -79.82mA
-981mV    -54mA      -55.88mA   -57.04mA
-817mV    -37mA      -35.13mA   -39.09mA
-489mV    -14.24mA   -14.03mA   -13.08mA
1.766V    47.58mA    44.68mA    44.9mA
2.217V    67.27mA    67.18mA    66.71mA
2.381V    85.6mA     113.1mA    78.52mA
2.504V    136mA      181.4mA    104.5mA
2.586V    187.6mA    236.1mA    148.1mA
2.7V      269.4mA    318mA      227.5mA
[Pullup]
|Voltage   I(typ)   I(min)   I(max)
-1.35V    261mA      280.3mA    250.5mA
-1.195V   147.5mA    170.6mA    133.8mA
-1.072V   74.23mA    96.25mA    62.23mA
-990mV    44.94mA    59.52mA    40.71mA
-867mV    29.86mA    31.47mA    30.65mA
-252mV    6.942mA    6.538mA    6.422mA
1.798V    -40.81mA   -39.31mA   -38.52mA
2.167V    -60.38mA   -60.19mA   -57.95mA
2.331V    -75.2mA    -82mA      -73.9mA
2.454V    -98.52mA   -125.8mA   -88.11mA
2.577V    -156.7mA   -194.5mA   -127.1mA
2.7V      -237.1mA   -275.9mA   -203.1mA
[Ramp]
| variable   typ   min   max
dV/dt_r   0.463/0.162n   0.435/0.218n   0.464/0.132n
dV/dt_f   0.472/0.112n   0.448/0.152n   0.469/95.429p
R_load = 50.000
[Rising Waveform]
R_fixture= 50.000
V_fixture= 0.0
V_fixture_min= 0.0
V_fixture_max= 0.0
|time   V(typ)   V(min)   V(max)
0s        1.224uV    6.848uV    563.4nV
398ps     -273.7uV   67.51uV    8.361mV
448ps     -1.856mV   9.691uV    98.13mV
522ps     13.49mV    -1.279mV   386.4mV
641ps     319.1mV    15.87mV    686.7mV
745ps     602.4mV    196.1mV    748.8mV
851ps     715.6mV    442.7mV    764.7mV
1.055ns   761mV      662.6mV    771.2mV
1.505ns   770.5mV    719.3mV    772.4mV
10ns      771.2mV    725.1mV    772.5mV
[Rising Waveform]
R_fixture= 50.000
V_fixture= 0.675
V_fixture_min= 0.656
V_fixture_max= 0.696
|time   V(typ)   V(min)   V(max)
0s        280.9mV    281.2mV    304.7mV
409ps     280.4mV    281.3mV    317.7mV
522ps     301mV      280.8mV    773.6mV
581ps     453.6mV    284.4mV    957.4mV
648ps     725mV      333.7mV    1.037V
714ps     914.2mV    488.8mV    1.065V
801ps     1.014V     734.9mV    1.077V
960ps     1.053V     955.4mV    1.082V
1.29ns    1.062V     1.013V     1.083V
10ns      1.063V     1.021V     1.083V
[Falling Waveform]
R_fixture= 50.000
V_fixture= 0.675
V_fixture_min= 0.656
V_fixture_max= 0.696
|time   V(typ)   V(min)   V(max)
0s        1.063V     1.02V      1.083V
389ps     1.063V     1.021V     1.082V
428ps     1.065V     1.021V     973.8mV
504ps     1.054V     1.023V     543.9mV
549ps     936.4mV    1.024V     409.1mV
630ps     517.7mV    965.5mV    331.9mV
742ps     321.4mV    569mV      309.8mV
862ps     290mV      341.3mV    305.7mV
1.142ns   281.6mV    286.3mV    304.7mV
10ns      280.9mV    281.2mV    304.7mV
[Falling Waveform]
R_fixture= 50.000
V_fixture= 0.0
V_fixture_min= 0.0
V_fixture_max= 0.0
|time   V(typ)   V(min)   V(max)
0s        771.2mV    725.1mV    772.5mV
387ps     772.6mV    725.3mV    770.2mV
422ps     774.5mV    725.8mV    671.4mV
496ps     761.3mV    728.7mV    243.7mV
535ps     654.5mV    728.7mV    114.3mV
617ps     212.3mV    665.3mV    26.61mV
726ps     30.87mV    243.7mV    4.311mV
822ps     7.322mV    53.73mV    766.4uV
1.032ns   316.6uV    3.497mV    -92.12uV
10ns      1.232uV    6.848uV    574.6nV
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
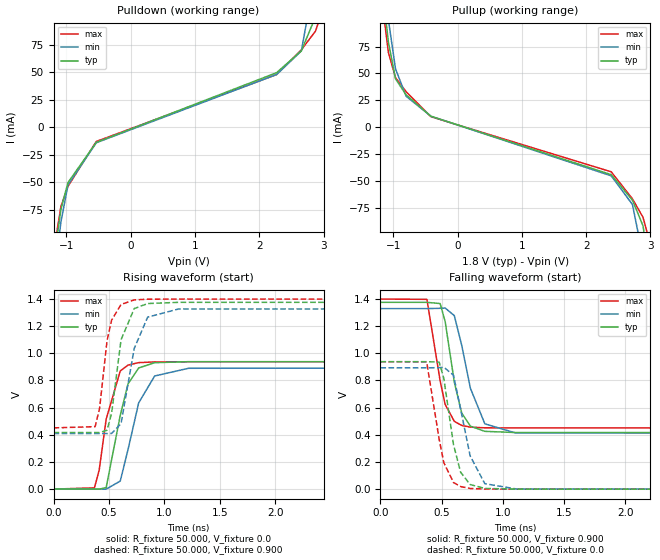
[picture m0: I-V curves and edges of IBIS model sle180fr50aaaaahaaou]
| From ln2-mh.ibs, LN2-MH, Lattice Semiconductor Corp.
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|   Model sle180fr50aaaaahaaou
[Model] sle180fr50aaaaahaaou
Model_type Output
Polarity   Non-Inverting
Enable   Active-High
Vmeas =  0.900V
Cref =  3.000pF
Rref =  50.000
Vref =  0.900V
C_comp   2.000pF   1.500pF   2.500pF
[Temperature Range]   25.000   0.125k   -40.000
[Voltage Range]   1.800V   1.750V   1.850V
[C Comp Corner]
C_comp   2.000pF   1.500pF   2.500pF
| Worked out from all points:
|   slope of the pulldown table from 0 to 0.27 V, typ, clamps not added: 42.9 ohm
|   slope of the pullup table from 0 to 0.27 V, typ, clamps not added: 44.7 ohm
|   rising waveform, R_fixture 50.000, V_fixture 0.0: 20-80 % time 128ps typ, 162ps min, 111ps max; typ from 0 V to 0.938 V
|   rising waveform, R_fixture 50.000, V_fixture 0.900: 20-80 % time 99.8ps typ, 125ps min, 89.8ps max; typ from 0.416 V to 1.37 V
|   falling waveform, R_fixture 50.000, V_fixture 0.900: 20-80 % time 108ps typ, 138ps min, 99.4ps max; typ from 1.37 V to 0.416 V
|   falling waveform, R_fixture 50.000, V_fixture 0.0: 20-80 % time 103ps typ, 126ps min, 98.9ps max; typ from 0.937 V to 0 V
[Pulldown]
|Voltage   I(typ)   I(min)   I(max)
-1.8V     -574.8mA   -575.6mA   -576.5mA
-1.195V   -127.5mA   -142.1mA   -120.6mA
-1.14V    -97.84mA   -111.9mA   -91.85mA
-1.085V   -74.68mA   -86.27mA   -72.09mA
-975mV    -50.36mA   -52.61mA   -53.75mA
-535mV    -13.85mA   -14.19mA   -13.01mA
2.27V     49.52mA    47.84mA    47.79mA
2.655V    69.4mA     69.25mA    70.29mA
2.875V    100.3mA    140.9mA    87.34mA
2.93V     124mA      172.9mA    96.87mA
3.04V     190.7mA    245.9mA    146mA
3.6V      634.1mA    681.8mA    589.7mA
[Pullup]
|Voltage   I(typ)   I(min)   I(max)
-1.8V     629.8mA    636.7mA    628.3mA
-1.185V   142.7mA    165.3mA    130mA
-1.13V    108.1mA    130.8mA    95.8mA
-1.075V   78.92mA    99.8mA     69.33mA
-965mV    44.98mA    54.25mA    46.09mA
-800mV    30.1mA     28.76mA    33.03mA
-415mV    10.14mA    10.21mA    9.741mA
2.39V     -44.25mA   -45.38mA   -41.61mA
2.72V     -68.04mA   -72.04mA   -66.77mA
2.885V    -91.94mA   -121.2mA   -84.04mA
2.995V    -137.8mA   -180.7mA   -108.3mA
3.6V      -578.8mA   -618.5mA   -540.2mA
[Ramp]
| variable   typ   min   max
dV/dt_r   0.563/0.128n   0.536/0.162n   0.562/0.112n
dV/dt_f   0.579/0.122n   0.556/0.163n   0.571/0.102n
R_load = 50.000
[Rising Waveform]
R_fixture= 50.000
V_fixture= 0.0
V_fixture_min= 0.0
V_fixture_max= 0.0
|time   V(typ)   V(min)   V(max)
0s        2.404uV    12.26uV    1.1uV
369ps     69.8uV     57.09uV    9.006mV
412ps     -496.6uV   80.08uV    139.9mV
475ps     11.27mV    -325uV     514.9mV
602ps     542.7mV    59.13mV    869.1mV
672ps     773.8mV    290.6mV    912.2mV
768ps     891.1mV    633.8mV    930.3mV
912ps     930mV      832mV      935.6mV
1.218ns   937.4mV    888.8mV    936.3mV
10ns      937.5mV    892.5mV    936.2mV
[Rising Waveform]
R_fixture= 50.000
V_fixture= 0.900
V_fixture_min= 0.874
V_fixture_max= 0.928
|time   V(typ)   V(min)   V(max)
0s        416.1mV    408.9mV    450.3mV
375ps     416.1mV    408.9mV    459.4mV
415ps     415.7mV    408.9mV    590.9mV
483ps     433.2mV    408.5mV    1.094V
524ps     558.7mV    409.3mV    1.243V
609ps     1.098V     481.5mV    1.358V
728ps     1.328V     1.035V     1.392V
849ps     1.365V     1.265V     1.397V
1.128ns   1.374V     1.325V     1.398V
10ns      1.374V     1.328V     1.398V
[Falling Waveform]
R_fixture= 50.000
V_fixture= 0.900
V_fixture_min= 0.874
V_fixture_max= 0.928
|time   V(typ)   V(min)   V(max)
0s        1.374V     1.328V     1.398V
380ps     1.374V     1.328V     1.396V
488ps     1.365V     1.33V      796.5mV
529ps     1.233V     1.332V     623mV
604ps     786.8mV    1.276V     498.6mV
664ps     560.2mV    1.059V     468.6mV
735ps     463.4mV    743mV      456.2mV
853ps     425.1mV    480.4mV    451.1mV
1.103ns   416.4mV    413.8mV    450.2mV
10ns      416.1mV    408.9mV    450.3mV
[Falling Waveform]
R_fixture= 50.000
V_fixture= 0.0
V_fixture_min= 0.0
V_fixture_max= 0.0
|time   V(typ)   V(min)   V(max)
0s        937.5mV    892.5mV    936.2mV
378ps     937.4mV    892.4mV    936.1mV
480ps     934.3mV    893.4mV    367.1mV
518ps     814.9mV    896.4mV    194.8mV
597ps     327.9mV    838.7mV    49.09mV
655ps     125mV      589.7mV    18.83mV
733ps     34.06mV    245.1mV    5.271mV
853ps     5.37mV     40.25mV    577.9uV
1.113ns   -57.16uV   1.121mV    -116.7uV
10ns      2.517uV    12.44uV    1.192uV
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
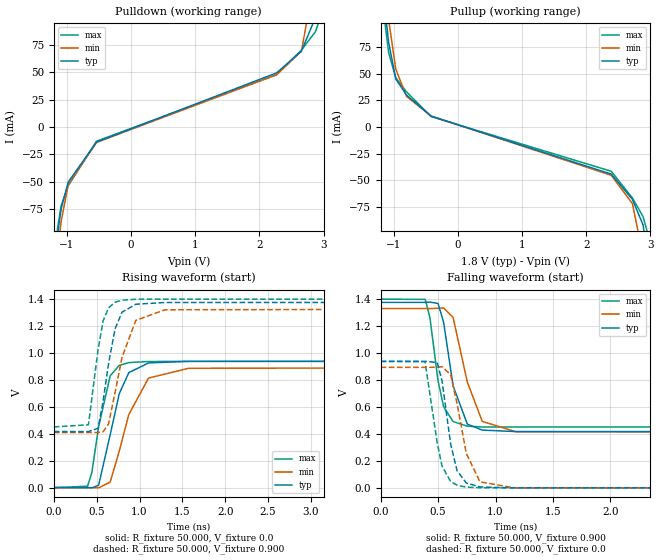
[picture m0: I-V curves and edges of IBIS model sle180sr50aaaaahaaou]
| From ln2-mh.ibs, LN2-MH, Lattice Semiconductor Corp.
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|   Model sle180sr50aaaaahaaou
[Model] sle180sr50aaaaahaaou
Model_type Output
Polarity   Non-Inverting
Enable   Active-High
Vmeas =  0.900V
Cref =  3.000pF
Rref =  50.000
Vref =  0.900V
C_comp   2.000pF   1.500pF   2.500pF
[Temperature Range]   25.000   0.125k   -40.000
[Voltage Range]   1.800V   1.750V   1.850V
[C Comp Corner]
C_comp   2.000pF   1.500pF   2.500pF
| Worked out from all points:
|   slope of the pulldown table from 0 to 0.27 V, typ, clamps not added: 42.9 ohm
|   slope of the pullup table from 0 to 0.27 V, typ, clamps not added: 44.7 ohm
|   rising waveform, R_fixture 50.000, V_fixture 0.0: 20-80 % time 193ps typ, 253ps min, 149ps max; typ from 0 V to 0.938 V
|   rising waveform, R_fixture 50.000, V_fixture 0.900: 20-80 % time 149ps typ, 194ps min, 118ps max; typ from 0.416 V to 1.37 V
|   falling waveform, R_fixture 50.000, V_fixture 0.900: 20-80 % time 111ps typ, 146ps min, 96.4ps max; typ from 1.37 V to 0.416 V
|   falling waveform, R_fixture 50.000, V_fixture 0.0: 20-80 % time 101ps typ, 125ps min, 94.7ps max; typ from 0.937 V to 0 V
[Pulldown]
|Voltage   I(typ)   I(min)   I(max)
-1.8V     -574.8mA   -575.6mA   -576.5mA
-1.195V   -127.5mA   -142.1mA   -120.6mA
-1.14V    -97.84mA   -111.9mA   -91.85mA
-1.085V   -74.68mA   -86.27mA   -72.09mA
-975mV    -50.36mA   -52.61mA   -53.75mA
-535mV    -13.85mA   -14.19mA   -13.01mA
2.27V     49.52mA    47.84mA    47.79mA
2.655V    69.4mA     69.25mA    70.29mA
2.875V    100.3mA    140.9mA    87.34mA
2.93V     124mA      172.9mA    96.87mA
3.04V     190.7mA    245.9mA    146mA
3.6V      634.1mA    681.8mA    589.7mA
[Pullup]
|Voltage   I(typ)   I(min)   I(max)
-1.8V     629.8mA    636.7mA    628.3mA
-1.185V   142.7mA    165.3mA    130mA
-1.13V    108.1mA    130.8mA    95.8mA
-1.075V   78.92mA    99.8mA     69.33mA
-965mV    44.98mA    54.25mA    46.09mA
-800mV    30.1mA     28.76mA    33.03mA
-415mV    10.14mA    10.21mA    9.741mA
2.39V     -44.25mA   -45.38mA   -41.61mA
2.72V     -68.04mA   -72.04mA   -66.77mA
2.885V    -91.94mA   -121.2mA   -84.04mA
2.995V    -137.8mA   -180.7mA   -108.3mA
3.6V      -578.8mA   -618.5mA   -540.2mA
[Ramp]
| variable   typ   min   max
dV/dt_r   0.563/0.194n   0.536/0.254n   0.562/0.149n
dV/dt_f   0.579/0.132n   0.556/0.184n   0.571/0.103n
R_load = 50.000
[Rising Waveform]
R_fixture= 50.000
V_fixture= 0.0
V_fixture_min= 0.0
V_fixture_max= 0.0
|time   V(typ)   V(min)   V(max)
0s        2.404uV    12.26uV    1.1uV
394ps     -180.4uV   73.23uV    10.72mV
443ps     -1.619mV   55.17uV    109.7mV
523ps     17.75mV    -1.468mV   451.9mV
658ps     393.2mV    41.77mV    829.8mV
764ps     696.9mV    271.7mV    906.6mV
875ps     852.8mV    542.1mV    927.3mV
1.105ns   924.9mV    812.6mV    935.2mV
1.574ns   936.8mV    885.2mV    936.2mV
10ns      937.5mV    892.5mV    936.2mV
[Rising Waveform]
R_fixture= 50.000
V_fixture= 0.900
V_fixture_min= 0.874
V_fixture_max= 0.928
|time   V(typ)   V(min)   V(max)
0s        416.1mV    408.9mV    450.3mV
404ps     415.7mV    408.9mV    466.1mV
516ps     440.1mV    408.6mV    1.023V
575ps     639.6mV    414.4mV    1.236V
638ps     917.6mV    471.3mV    1.333V
715ps     1.178V     706.3mV    1.375V
796ps     1.301V     965.7mV    1.39V
956ps     1.36V      1.24V      1.397V
1.296ns   1.373V     1.319V     1.398V
10ns      1.374V     1.328V     1.398V
[Falling Waveform]
R_fixture= 50.000
V_fixture= 0.900
V_fixture_min= 0.874
V_fixture_max= 0.928
|time   V(typ)   V(min)   V(max)
0s        1.374V     1.328V     1.398V
388ps     1.374V     1.328V     1.396V
429ps     1.376V     1.328V     1.258V
499ps     1.366V     1.33V      793.5mV
548ps     1.226V     1.333V     600mV
630ps     756.1mV    1.263V     491mV
754ps     472.2mV    783.7mV    456.8mV
884ps     427.8mV    492.1mV    451.2mV
1.174ns   416.8mV    416mV      450.2mV
10ns      416.1mV    408.9mV    450.3mV
[Falling Waveform]
R_fixture= 50.000
V_fixture= 0.0
V_fixture_min= 0.0
V_fixture_max= 0.0
|time   V(typ)   V(min)   V(max)
0s        937.5mV    892.5mV    936.2mV
386ps     937.5mV    892.5mV    934.4mV
492ps     928.1mV    893.9mV    333.6mV
534ps     791.6mV    897mV      161.2mV
609ps     323.9mV    838.8mV    46.15mV
665ps     126.2mV    623.1mV    19.09mV
745ps     35.77mV    255.5mV    5.44mV
864ps     6.79mV     44.36mV    602.2uV
1.154ns   -101.3uV   1.323mV    -149.2uV
10ns      2.506uV    12.43uV    1.182uV
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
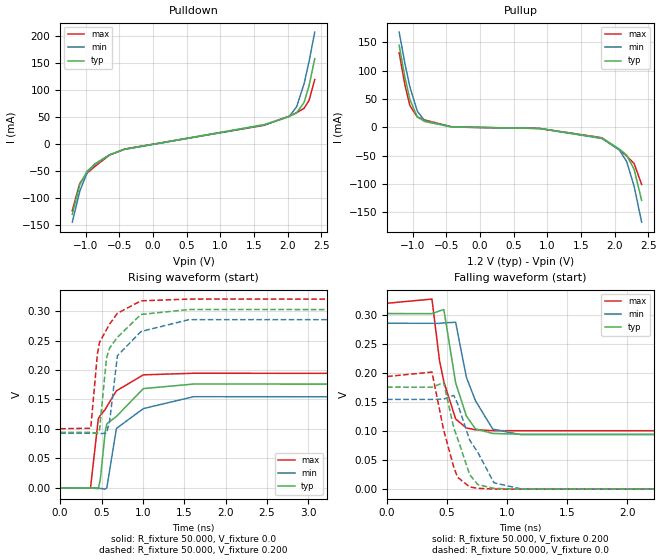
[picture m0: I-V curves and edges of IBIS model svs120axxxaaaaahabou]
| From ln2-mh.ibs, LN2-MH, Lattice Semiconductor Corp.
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|   Model svs120axxxaaaaahabou
[Model] svs120axxxaaaaahabou
Model_type Output
Polarity   Non-Inverting
Enable   Active-High
Vmeas =  0.200V
Cref =  3.000pF
Rref =  50.000
Vref =  0.200V
C_comp   2.000pF   1.500pF   2.500pF
[Temperature Range]   25.000   0.125k   -40.000
[Voltage Range]   1.200V   1.160V   1.240V
[C Comp Corner]
C_comp   2.000pF   1.500pF   2.500pF
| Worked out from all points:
|   slope of the pulldown table from 0 to 0.18 V, typ, clamps not added: 44.6 ohm
|   rising waveform, R_fixture 50.000, V_fixture 0.0: 20-80 % time 268ps typ, 316ps min, 231ps max; typ from 0 V to 0.176 V
|   rising waveform, R_fixture 50.000, V_fixture 0.200: 20-80 % time 207ps typ, 229ps min, 182ps max; typ from 0.094 V to 0.302 V
|   falling waveform, R_fixture 50.000, V_fixture 0.200: 20-80 % time 133ps typ, 180ps min, 123ps max; typ from 0.302 V to 0.094 V
|   falling waveform, R_fixture 50.000, V_fixture 0.0: 20-80 % time 153ps typ, 211ps min, 141ps max; typ from 0.176 V to 0 V
[Pulldown]
|Voltage   I(typ)   I(min)   I(max)
-1.2V     -129.9mA   -144.4mA   -123mA
-1.089V   -75.23mA   -87.23mA   -72.53mA
-978mV    -49.79mA   -52.4mA    -53.58mA
-867mV    -37.92mA   -36.78mA   -41.44mA
-645mV    -19.61mA   -19.66mA   -20.2mA
-423mV    -9.6mA     -9.688mA   -9.034mA
1.649V    36.08mA    35.19mA    34.89mA
2.019V    51mA       51.05mA    51.71mA
2.13V     57.74mA    68.71mA    58.04mA
2.241V    76.87mA    111.3mA    66.2mA
2.315V    107.7mA    152.5mA    80.67mA
2.4V      158mA      207.2mA    119.5mA
[Pullup]
|Voltage   I(typ)   I(min)   I(max)
-1.2V     145mA      168.2mA    131.8mA
-1.115V   88.92mA    113.2mA    75.19mA
-1.041V   49.32mA    71.62mA    38.6mA
-930mV    18.16mA    28.51mA    18.3mA
-819mV    10.42mA    11.39mA    13.05mA
-412mV    553.3uA    727.4uA    759.6uA
883mV     -1.884mA   -1.883mA   -1.824mA
1.808V    -18.63mA   -19.57mA   -18.16mA
2.067V    -37.99mA   -39.63mA   -39.41mA
2.178V    -49.13mA   -60.29mA   -50.42mA
2.289V    -74.15mA   -104.2mA   -63.88mA
2.4V      -128.8mA   -167.3mA   -100.6mA
[Ramp]
| variable   typ   min   max
dV/dt_r   0.105/0.268n   92.656m/0.316n   0.116/0.231n
dV/dt_f   0.380/0.108n   0.364/0.141n   0.382/85.839p
R_load = 50.000
[Rising Waveform]
R_fixture= 50.000
V_fixture= 0.0
V_fixture_min= 0.0
V_fixture_max= 0.0
|time   V(typ)   V(min)   V(max)
0s        1.294uV    7.02uV     589.9nV
367ps     66.61uV    51.93uV    -272.8uV
461ps     -1.271mV   -136.7uV   117.3mV
485ps     13.61mV    -745.8uV   122.9mV
543ps     93.41mV    -2.068mV   132.8mV
564ps     108.7mV    78.78uV    137.8mV
680ps     121.3mV    100.9mV    164.7mV
1.006ns   168.5mV    134.6mV    191.8mV
1.612ns   176.2mV    154.7mV    194.5mV
10ns      175.5mV    154.4mV    193.8mV
[Rising Waveform]
R_fixture= 50.000
V_fixture= 0.200
V_fixture_min= 0.195
V_fixture_max= 0.207
|time   V(typ)   V(min)   V(max)
0s        94.23mV    92.68mV    100.5mV
370ps     94.28mV    92.73mV    101.2mV
450ps     92.72mV    92.65mV    226.7mV
476ps     98.72mV    92.22mV    247mV
560ps     220.3mV    92.71mV    268.4mV
599ps     237.5mV    113.9mV    277.9mV
692ps     255.5mV    224.2mV    296.2mV
977ps     294.2mV    265.3mV    317.3mV
1.558ns   302.6mV    285.4mV    320.3mV
10ns      302.1mV    285.4mV    319.8mV
[Falling Waveform]
R_fixture= 50.000
V_fixture= 0.200
V_fixture_min= 0.195
V_fixture_max= 0.207
|time   V(typ)   V(min)   V(max)
0s        302.1mV    285.4mV    319.8mV
374ps     301.9mV    285.3mV    327mV
437ps     306.6mV    285.2mV    220.9mV
473ps     309mV      286mV      184.8mV
571ps     183mV      287.2mV    120.8mV
660ps     126mV      192.8mV    105.3mV
736ps     103.6mV    152.1mV    102.2mV
880ps     95.88mV    103.3mV    100.7mV
1.11ns    94.4mV     93.9mV     100.5mV
10ns      94.23mV    92.68mV    100.5mV
[Falling Waveform]
R_fixture= 50.000
V_fixture= 0.0
V_fixture_min= 0.0
V_fixture_max= 0.0
|time   V(typ)   V(min)   V(max)
0s        175.5mV    154.4mV    193.8mV
374ps     175.4mV    154.4mV    201.4mV
471ps     183.3mV    154.9mV    102mV
556ps     105.1mV    161.4mV    37.26mV
588ps     86.86mV    146.8mV    20.25mV
688ps     24.96mV    84.36mV    3.898mV
756ps     7.858mV    63.12mV    1.443mV
890ps     1.307mV    10.91mV    220.5uV
1.11ns    111.6uV    782.8uV    -5.706uV
10ns      2.364uV    8.48uV     1.467uV
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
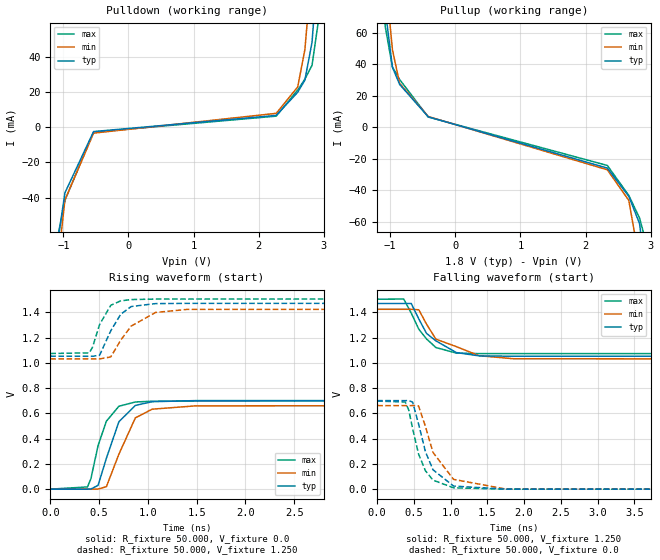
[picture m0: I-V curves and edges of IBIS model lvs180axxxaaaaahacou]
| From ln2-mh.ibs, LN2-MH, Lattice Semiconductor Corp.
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|   Model lvs180axxxaaaaahacou
[Model] lvs180axxxaaaaahacou
Model_type Output
Polarity   Non-Inverting
Enable   Active-High
Vmeas =  1.250V
Cref =  3.000pF
Rref =  50.000
Vref =  1.250V
C_comp   2.000pF   1.500pF   2.500pF
[Temperature Range]   25.000   0.125k   -40.000
[Voltage Range]   1.800V   1.750V   1.850V
[C Comp Corner]
C_comp   2.000pF   1.500pF   2.500pF
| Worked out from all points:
|   slope of the pullup table from 0 to 0.27 V, typ, clamps not added: 74.2 ohm
|   rising waveform, R_fixture 50.000, V_fixture 0.0: 20-80 % time 183ps typ, 190ps min, 155ps max; typ from 0 V to 0.702 V
|   rising waveform, R_fixture 50.000, V_fixture 1.250: 20-80 % time 164ps typ, 253ps min, 128ps max; typ from 1.05 V to 1.47 V
|   falling waveform, R_fixture 50.000, V_fixture 1.250: 20-80 % time 351ps typ, 507ps min, 274ps max; typ from 1.47 V to 1.05 V
|   falling waveform, R_fixture 50.000, V_fixture 0.0: 20-80 % time 227ps typ, 303ps min, 207ps max; typ from 0.702 V to 0 V
[Pulldown]
|Voltage   I(typ)   I(min)   I(max)
-1.8V     -571.7mA   -572.5mA   -573.8mA
-1.14V    -90.15mA   -105mA     -84.26mA
-1.085V   -64.88mA   -77.95mA   -61.92mA
-975mV    -37.2mA    -41.2mA    -41.47mA
-535mV    -2.503mA   -3.387mA   -2.832mA
2.27V     6.633mA    7.817mA    6.235mA
2.6V      19.76mA    22.76mA    21.03mA
2.71V     26.61mA    43.81mA    27.18mA
2.82V     48.02mA    90.95mA    35.02mA
2.93V     102.3mA    157.5mA    63.15mA
2.985V    138mA      195mA      92.73mA
3.6V      627.5mA    675.4mA    583.4mA
[Pullup]
|Voltage   I(typ)   I(min)   I(max)
-1.8V     628.7mA    635.8mA    627.1mA
-1.13V    104.6mA    127.9mA    91.66mA
-1.075V   74.29mA    96.32mA    63.5mA
-965mV    37.91mA    49.04mA    38.1mA
-855mV    27.1mA     27.77mA    30.22mA
-415mV    6.538mA    6.728mA    6.407mA
2.335V    -25.96mA   -27.05mA   -24.3mA
2.665V    -43.94mA   -46.48mA   -43.3mA
2.83V     -61.14mA   -85.14mA   -57.67mA
2.94V     -98.34mA   -139.8mA   -74.56mA
2.995V    -128mA     -172.9mA   -94.69mA
3.6V      -575.5mA   -615.2mA   -536.9mA
[Ramp]
| variable   typ   min   max
dV/dt_r   0.421/0.183n   0.397/0.190n   0.419/0.155n
dV/dt_f   0.133/0.526n   0.125/0.748n   0.143/0.389n
R_load = 50.000
[Rising Waveform]
R_fixture= 50.000
V_fixture= 0.0
V_fixture_min= 0.0
V_fixture_max= 0.0
|time   V(typ)   V(min)   V(max)
0s        5.673uV    28.54uV    2.469uV
381ps     52.94uV    188.2uV    17.81mV
416ps     884.8uV    243.9uV    81.95mV
490ps     30.27mV    703.6uV    346.3mV
575ps     245.3mV    19.75mV    538.3mV
703ps     533.8mV    277mV      656.5mV
872ps     663.1mV    564.7mV    690.2mV
1.045ns   692.4mV    633.3mV    696.1mV
1.492ns   701.2mV    659.7mV    697.9mV
10ns      701.5mV    662.3mV    697.9mV
[Rising Waveform]
R_fixture= 50.000
V_fixture= 1.250
V_fixture_min= 1.213
V_fixture_max= 1.289
|time   V(typ)   V(min)   V(max)
0s        1.053V     1.031V     1.074V
400ps     1.052V     1.031V     1.079V
433ps     1.052V     1.031V     1.124V
505ps     1.06V      1.031V     1.303V
620ps     1.254V     1.047V     1.456V
722ps     1.385V     1.18V      1.491V
829ps     1.446V     1.291V     1.501V
1.079ns   1.469V     1.399V     1.505V
1.401ns   1.471V     1.423V     1.505V
10ns      1.471V     1.425V     1.505V
[Falling Waveform]
R_fixture= 50.000
V_fixture= 1.250
V_fixture_min= 1.213
V_fixture_max= 1.289
|time   V(typ)   V(min)   V(max)
0s        1.471V     1.425V     1.505V
362ps     1.471V     1.425V     1.506V
464ps     1.471V     1.425V     1.395V
567ps     1.348V     1.421V     1.267V
672ps     1.234V     1.307V     1.19V
800ps     1.175V     1.188V     1.122V
1.078ns   1.082V     1.129V     1.078V
1.389ns   1.056V     1.057V     1.074V
1.861ns   1.053V     1.033V     1.074V
10ns      1.053V     1.031V     1.074V
[Falling Waveform]
R_fixture= 50.000
V_fixture= 0.0
V_fixture_min= 0.0
V_fixture_max= 0.0
|time   V(typ)   V(min)   V(max)
0s        701.5mV    662.3mV    697.8mV
382ps     701.3mV    662.3mV    690.3mV
430ps     702.3mV    662.2mV    627.2mV
483ps     689.4mV    662.5mV    479mV
563ps     517.7mV    660.3mV    279.1mV
657ps     296.9mV    496.8mV    145.9mV
760ps     153.7mV    291.1mV    71.67mV
1.04ns    24.56mV    77.55mV    10.62mV
1.75ns    246.8uV    1.125mV    113.9uV
10ns      6.239uV    29.65uV    2.685uV
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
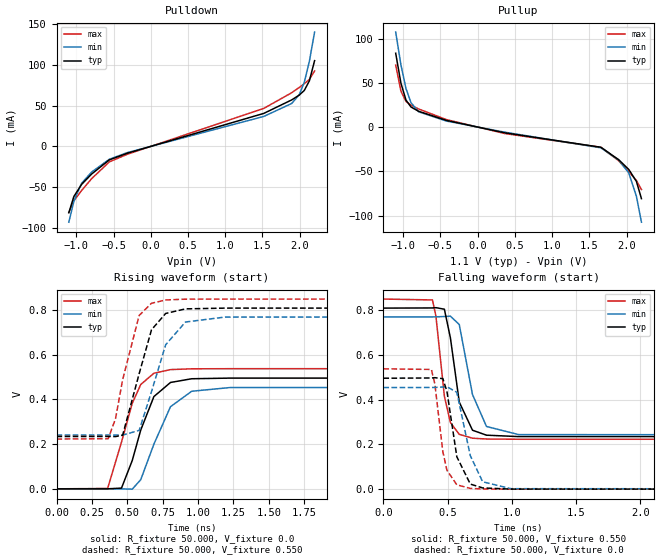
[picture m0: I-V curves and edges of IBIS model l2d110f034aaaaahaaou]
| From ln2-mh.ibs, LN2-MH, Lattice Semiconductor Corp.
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|   Model l2d110f034aaaaahaaou
[Model] l2d110f034aaaaahaaou
Model_type Output
Polarity   Non-Inverting
Enable   Active-High
Vmeas =  0.550V
Cref =  20.000pF
Rref =  50.000
Vref =  0.600V
C_comp   2.000pF   1.500pF   2.500pF
[Temperature Range]   25.000   0.125k   -40.000
[Voltage Range]   1.100V   1.070V   1.130V
[C Comp Corner]
C_comp   2.000pF   1.500pF   2.500pF
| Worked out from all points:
|   slope of the pulldown table from 0 to 0.165 V, typ, clamps not added: 37.1 ohm
|   slope of the pullup table from 0 to 0.165 V, typ, clamps not added: 55.5 ohm
|   rising waveform, R_fixture 50.000, V_fixture 0.0: 20-80 % time 151ps typ, 173ps min, 144ps max; typ from 0 V to 0.496 V
|   rising waveform, R_fixture 50.000, V_fixture 0.550: 20-80 % time 129ps typ, 148ps min, 121ps max; typ from 0.234 V to 0.809 V
|   falling waveform, R_fixture 50.000, V_fixture 0.550: 20-80 % time 90.3ps typ, 111ps min, 77.2ps max; typ from 0.809 V to 0.234 V
|   falling waveform, R_fixture 50.000, V_fixture 0.0: 20-80 % time 85.9ps typ, 105ps min, 74.4ps max; typ from 0.496 V to 0 V
[Pulldown]
|Voltage   I(typ)   I(min)   I(max)
-1.1V     -81.59mA   -93.17mA   -81.22mA
-1.032V   -61.62mA   -67.46mA   -66.97mA
-930mV    -46.97mA   -45.58mA   -54.42mA
-794mV    -34.04mA   -31.61mA   -39.78mA
-556mV    -16.66mA   -15.87mA   -19.1mA
-318mV    -8.586mA   -7.811mA   -9.863mA
1.518V    40.44mA    36.73mA    46.57mA
1.892V    56.98mA    52.59mA    65.78mA
1.994V    62.92mA    63.32mA    72.3mA
2.062V    68.66mA    78.75mA    76.84mA
2.13V     80.38mA    104.4mA    82.16mA
2.2V      105.2mA    140.3mA    92.49mA
[Pullup]
|Voltage   I(typ)   I(min)   I(max)
-1.1V     83.6mA     107.5mA    70.17mA
-1.03V    49.84mA    70.54mA    40.88mA
-962mV    30.67mA    43.73mA    29.06mA
-894mV    22.74mA    27.56mA    24.79mA
-792mV    17.97mA    17.43mA    20.61mA
-418mV    7.65mA     6.925mA    8.54mA
364mV     -6.384mA   -5.65mA    -7.161mA
1.656V    -22.72mA   -23.36mA   -22.74mA
1.894V    -36.76mA   -37.21mA   -37.99mA
2.03V     -47.82mA   -51.73mA   -50.2mA
2.132V    -61.22mA   -78.08mA   -60.36mA
2.2V      -80.8mA    -107.4mA   -70.51mA
[Ramp]
| variable   typ   min   max
dV/dt_r   0.297/0.151n   0.272/0.173n   0.323/0.143n
dV/dt_f   0.379/97.227p   0.352/0.122n   0.412/81.798p
R_load = 50.000
[Rising Waveform]
R_fixture= 50.000
V_fixture= 0.0
V_fixture_min= 0.0
V_fixture_max= 0.0
|time   V(typ)   V(min)   V(max)
0s        1.065uV    6.127uV    432.2nV
361ps     70.58uV    47.47uV    1.675mV
459ps     3.285mV    -102.3uV   209.2mV
535ps     126.7mV    -1.498mV   382.6mV
595ps     263.2mV    40.97mV    466.9mV
688ps     412.9mV    200.1mV    517.3mV
805ps     475.9mV    367.4mV    533.5mV
955ps     492.6mV    436.7mV    537.1mV
1.225ns   495.5mV    453.2mV    537.6mV
10ns      495.6mV    454mV      537.6mV
[Rising Waveform]
R_fixture= 50.000
V_fixture= 0.550
V_fixture_min= 0.534
V_fixture_max= 0.568
|time   V(typ)   V(min)   V(max)
0s        234.3mV    240.5mV    222.8mV
365ps     234.4mV    240.5mV    224.3mV
417ps     233.8mV    240.6mV    314mV
467ps     239.9mV    240.3mV    488.1mV
584ps     515.7mV    261.5mV    776.2mV
671ps     711.8mV    434.8mV    830.4mV
771ps     784.7mV    644.7mV    845.2mV
911ps     805.3mV    746.5mV    848.7mV
1.191ns   808.7mV    768.7mV    849.2mV
10ns      808.7mV    769.4mV    849.1mV
[Falling Waveform]
R_fixture= 50.000
V_fixture= 0.550
V_fixture_min= 0.534
V_fixture_max= 0.568
|time   V(typ)   V(min)   V(max)
0s        808.7mV    769.4mV    849.1mV
382ps     809.4mV    769.5mV    845.2mV
409ps     810.7mV    769.7mV    773.7mV
475ps     803.8mV    771.1mV    415mV
522ps     675.7mV    772.7mV    297.7mV
591ps     388.9mV    735.3mV    244.9mV
694ps     263.3mV    422.8mV    227.6mV
803ps     241.1mV    280mV      224mV
1.053ns   234.8mV    243.7mV    222.9mV
10ns      234.3mV    240.5mV    222.8mV
[Falling Waveform]
R_fixture= 50.000
V_fixture= 0.0
V_fixture_min= 0.0
V_fixture_max= 0.0
|time   V(typ)   V(min)   V(max)
0s        495.5mV    454mV      537.5mV
374ps     496.6mV    454.1mV    534.7mV
401ps     498mV      454.4mV    469.3mV
463ps     493.6mV    456.1mV    167.3mV
495ps     436.8mV    457.5mV    84.41mV
572ps     144.7mV    432.6mV    19.21mV
677ps     22.7mV     149.8mV    3.466mV
773ps     5.524mV    33.05mV    792.9uV
993ps     270.5uV    2.163mV    -33uV
10ns      1.066uV    6.117uV    437.2nV
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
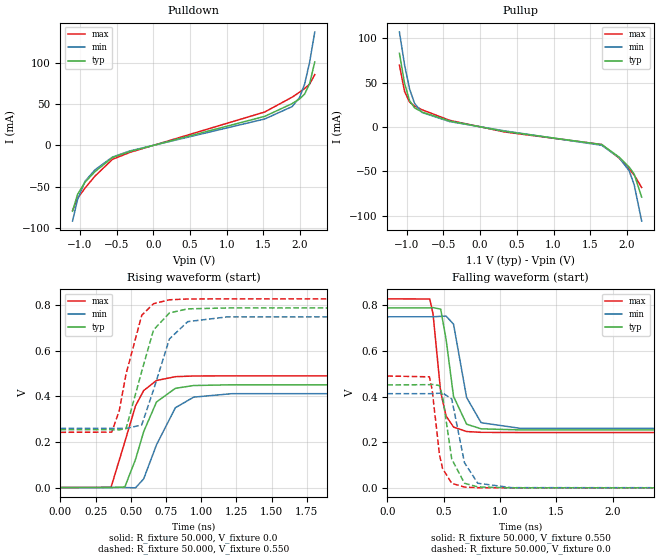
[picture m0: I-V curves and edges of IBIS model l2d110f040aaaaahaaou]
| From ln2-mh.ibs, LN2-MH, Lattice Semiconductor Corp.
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|   Model l2d110f040aaaaahaaou
[Model] l2d110f040aaaaahaaou
Model_type Output
Polarity   Non-Inverting
Enable   Active-High
Vmeas =  0.550V
Cref =  20.000pF
Rref =  50.000
Vref =  0.600V
C_comp   2.000pF   1.500pF   2.500pF
[Temperature Range]   25.000   0.125k   -40.000
[Voltage Range]   1.100V   1.070V   1.130V
[C Comp Corner]
C_comp   2.000pF   1.500pF   2.500pF
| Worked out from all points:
|   slope of the pulldown table from 0 to 0.165 V, typ, clamps not added: 42.8 ohm
|   slope of the pullup table from 0 to 0.165 V, typ, clamps not added: 64.5 ohm
|   rising waveform, R_fixture 50.000, V_fixture 0.0: 20-80 % time 150ps typ, 168ps min, 143ps max; typ from 0 V to 0.451 V
|   rising waveform, R_fixture 50.000, V_fixture 0.550: 20-80 % time 126ps typ, 141ps min, 119ps max; typ from 0.254 V to 0.788 V
|   falling waveform, R_fixture 50.000, V_fixture 0.550: 20-80 % time 92.7ps typ, 112ps min, 79.4ps max; typ from 0.788 V to 0.254 V
|   falling waveform, R_fixture 50.000, V_fixture 0.0: 20-80 % time 88.3ps typ, 104ps min, 76.5ps max; typ from 0.451 V to 0 V
[Pulldown]
|Voltage   I(typ)   I(min)   I(max)
-1.1V     -79.96mA   -91.87mA   -79.09mA
-1.032V   -59.57mA   -65.87mA   -64.43mA
-930mV    -44.73mA   -43.66mA   -51.86mA
-794mV    -31.89mA   -29.69mA   -37.36mA
-556mV    -14.81mA   -14.23mA   -16.99mA
-318mV    -7.449mA   -6.777mA   -8.559mA
1.518V    35.14mA    31.97mA    40.44mA
1.892V    50.64mA    47.02mA    58.47mA
1.994V    56.37mA    58.13mA    64.65mA
2.062V    62.28mA    74.36mA    68.99mA
2.13V     74.93mA    100.9mA    74.33mA
2.2V      101.2mA    137.5mA    85.79mA
[Pullup]
|Voltage   I(typ)   I(min)   I(max)
-1.1V     83.04mA    107mA      69.59mA
-1.03V    49.05mA    69.88mA    39.98mA
-962mV    29.63mA    42.86mA    27.91mA
-894mV    21.56mA    26.55mA    23.58mA
-792mV    16.75mA    16.31mA    19.39mA
-418mV    6.661mA    6.061mA    7.463mA
330mV     -5.014mA   -4.428mA   -5.641mA
1.656V    -19.9mA    -20.72mA   -19.81mA
1.894V    -34.07mA   -34.69mA   -35.26mA
2.03V     -45.27mA   -49.5mA    -47.61mA
2.098V    -53.07mA   -65.07mA   -54.23mA
2.2V      -79.11mA   -106.1mA   -68.33mA
[Ramp]
| variable   typ   min   max
dV/dt_r   0.271/0.150n   0.247/0.168n   0.294/0.143n
dV/dt_f   0.355/99.436p   0.330/0.123n   0.389/83.778p
R_load = 50.000
[Rising Waveform]
R_fixture= 50.000
V_fixture= 0.0
V_fixture_min= 0.0
V_fixture_max= 0.0
|time   V(typ)   V(min)   V(max)
0s        1.175uV    6.716uV    479.8nV
359ps     73.19uV    52.84uV    867.9uV
457ps     2.311mV    -72.72uV   200.1mV
533ps     123.3mV    -1.385mV   358.1mV
591ps     245mV      38.03mV    425.5mV
682ps     375.4mV    187.3mV    469.7mV
816ps     435.2mV    350.1mV    486.4mV
946ps     447.6mV    396.6mV    489.4mV
1.216ns   450.8mV    411.7mV    490mV
10ns      450.8mV    412.4mV    490mV
[Rising Waveform]
R_fixture= 50.000
V_fixture= 0.550
V_fixture_min= 0.534
V_fixture_max= 0.568
|time   V(typ)   V(min)   V(max)
0s        253.6mV    259.5mV    242.3mV
364ps     253.7mV    259.6mV    243.2mV
417ps     253.2mV    259.6mV    335.2mV
466ps     258.5mV    259.3mV    498.6mV
577ps     509.3mV    274.5mV    755.3mV
661ps     691.5mV    428.9mV    806.7mV
774ps     766.1mV    652mV      823.8mV
904ps     784mV      727.9mV    827.3mV
1.184ns   787.9mV    748.7mV    827.8mV
10ns      787.9mV    749.4mV    827.8mV
[Falling Waveform]
R_fixture= 50.000
V_fixture= 0.550
V_fixture_min= 0.534
V_fixture_max= 0.568
|time   V(typ)   V(min)   V(max)
0s        787.9mV    749.4mV    827.8mV
377ps     788.4mV    749.4mV    827.2mV
406ps     789.6mV    749.6mV    761.4mV
474ps     782.8mV    751mV      418.7mV
522ps     649.6mV    752.4mV    314.9mV
588ps     400.4mV    717mV      266.3mV
704ps     278.8mV    395.7mV    246.7mV
833ps     258.5mV    285.3mV    243.1mV
1.183ns   253.7mV    260.5mV    242.3mV
10ns      253.6mV    259.5mV    242.3mV
[Falling Waveform]
R_fixture= 50.000
V_fixture= 0.0
V_fixture_min= 0.0
V_fixture_max= 0.0
|time   V(typ)   V(min)   V(max)
0s        450.8mV    412.4mV    489.9mV
374ps     451.9mV    412.4mV    486.2mV
398ps     453mV      412.7mV    429.9mV
463ps     448.1mV    414.5mV    145.8mV
491ps     400.7mV    415.7mV    83.94mV
572ps     126mV      389.3mV    19.76mV
685ps     20.21mV    110.3mV    3.414mV
803ps     3.979mV    20.11mV    563.5uV
1.103ns   6.069uV    708.5uV    -68.91uV
10ns      1.177uV    6.709uV    485.4nV
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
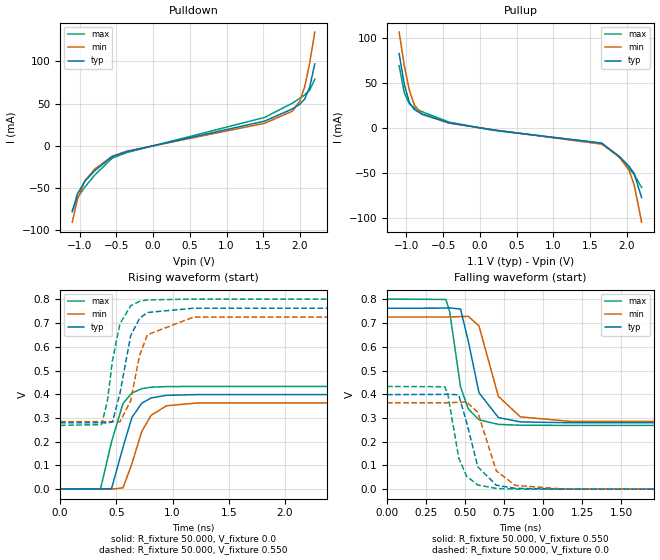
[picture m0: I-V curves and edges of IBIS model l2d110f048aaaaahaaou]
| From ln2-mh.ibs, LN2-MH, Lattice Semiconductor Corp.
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|   Model l2d110f048aaaaahaaou
[Model] l2d110f048aaaaahaaou
Model_type Output
Polarity   Non-Inverting
Enable   Active-High
Vmeas =  0.550V
Cref =  20.000pF
Rref =  50.000
Vref =  0.600V
C_comp   2.000pF   1.500pF   2.500pF
[Temperature Range]   25.000   0.125k   -40.000
[Voltage Range]   1.100V   1.070V   1.130V
[C Comp Corner]
C_comp   2.000pF   1.500pF   2.500pF
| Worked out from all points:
|   slope of the pulldown table from 0 to 0.165 V, typ, clamps not added: 51.7 ohm
|   slope of the pullup table from 0 to 0.165 V, typ, clamps not added: 77.4 ohm
|   rising waveform, R_fixture 50.000, V_fixture 0.0: 20-80 % time 144ps typ, 162ps min, 134ps max; typ from 0 V to 0.399 V
|   rising waveform, R_fixture 50.000, V_fixture 0.550: 20-80 % time 119ps typ, 134ps min, 109ps max; typ from 0.28 V to 0.763 V
|   falling waveform, R_fixture 50.000, V_fixture 0.550: 20-80 % time 97.1ps typ, 117ps min, 82.6ps max; typ from 0.763 V to 0.28 V
|   falling waveform, R_fixture 50.000, V_fixture 0.0: 20-80 % time 92.8ps typ, 108ps min, 79.7ps max; typ from 0.399 V to 0 V
[Pulldown]
|Voltage   I(typ)   I(min)   I(max)
-1.1V     -78.14mA   -90.41mA   -76.7mA
-1.032V   -57.25mA   -64.07mA   -61.57mA
-930mV    -42.18mA   -41.5mA    -48.97mA
-794mV    -29.46mA   -27.52mA   -34.62mA
-556mV    -12.72mA   -12.38mA   -14.61mA
-352mV    -6.823mA   -6.248mA   -7.842mA
1.518V    29.15mA    26.61mA    33.53mA
1.892V    43.47mA    40.78mA    50.24mA
1.994V    48.99mA    52.39mA    56.03mA
2.062V    55.16mA    69.53mA    60.16mA
2.13V     68.97mA    97.07mA    65.62mA
2.2V      96.87mA    134.5mA    78.6mA
[Pullup]
|Voltage   I(typ)   I(min)   I(max)
-1.1V     82.47mA    106.4mA    68.98mA
-1.03V    48.25mA    69.21mA    39.04mA
-962mV    28.56mA    42.03mA    26.72mA
-894mV    20.36mA    25.52mA    22.34mA
-792mV    15.52mA    15.17mA    18.14mA
-418mV    5.653mA    5.18mA     6.352mA
194mV     -2.501mA   -2.203mA   -2.816mA
1.656V    -17.03mA   -18.06mA   -16.81mA
1.894V    -31.36mA   -32.15mA   -32.48mA
2.03V     -42.69mA   -47.23mA   -44.96mA
2.098V    -50.65mA   -63.14mA   -51.63mA
2.2V      -77.38mA   -104.7mA   -66.08mA
[Ramp]
| variable   typ   min   max
dV/dt_r   0.239/0.144n   0.219/0.162n   0.260/0.135n
dV/dt_f   0.324/0.104n   0.299/0.129n   0.357/86.975p
R_load = 50.000
[Rising Waveform]
R_fixture= 50.000
V_fixture= 0.0
V_fixture_min= 0.0
V_fixture_max= 0.0
|time   V(typ)   V(min)   V(max)
0s        1.321uV    7.484uV    543nV
359ps     79.67uV    60.66uV    799uV
457ps     2.256mV    -65.24uV   199.5mV
559ps     176.9mV    5.733mV    361.4mV
638ps     302.2mV    107.3mV    405.4mV
726ps     362.6mV    243.3mV    423.6mV
809ps     384.6mV    311.5mV    429.8mV
946ps     395.8mV    351.5mV    432.6mV
1.226ns   398.7mV    363.8mV    433.2mV
10ns      398.7mV    364.3mV    433.1mV
[Rising Waveform]
R_fixture= 50.000
V_fixture= 0.550
V_fixture_min= 0.534
V_fixture_max= 0.568
|time   V(typ)   V(min)   V(max)
0s        279.8mV    284.9mV    268.9mV
368ps     279.8mV    284.9mV    272.1mV
420ps     279.3mV    285mV      370.6mV
465ps     283.6mV    284.7mV    542.4mV
532ps     404.1mV    284.2mV    697.3mV
627ps     647.1mV    372.8mV    773.4mV
706ps     719.8mV    563.4mV    792mV
776ps     744.9mV    651.4mV    798mV
1.186ns   763mV      725.3mV    801.6mV
10ns      763mV      726mV      801.6mV
[Falling Waveform]
R_fixture= 50.000
V_fixture= 0.550
V_fixture_min= 0.534
V_fixture_max= 0.568
|time   V(typ)   V(min)   V(max)
0s        763mV      726mV      801.6mV
377ps     763.5mV    726mV      800.1mV
401ps     764.4mV    726.1mV    748.4mV
471ps     759.2mV    727.4mV    430mV
521ps     621.8mV    728.8mV    337.9mV
589ps     406.8mV    687.9mV    292.6mV
713ps     301.9mV    391.1mV    273mV
854ps     283.6mV    304.7mV    269.5mV
1.174ns   279.8mV    285.8mV    268.9mV
10ns      279.8mV    284.9mV    268.9mV
[Falling Waveform]
R_fixture= 50.000
V_fixture= 0.0
V_fixture_min= 0.0
V_fixture_max= 0.0
|time   V(typ)   V(min)   V(max)
0s        398.7mV    364.3mV    433.1mV
370ps     399.6mV    364.3mV    431.9mV
391ps     400.5mV    364.5mV    393.9mV
459ps     397.7mV    366.1mV    132.1mV
509ps     283.4mV    367.6mV    54.97mV
581ps     94.24mV    324.3mV    17.4mV
700ps     16.55mV    76.95mV    3.084mV
821ps     3.495mV    15.9mV     517.8uV
1.13ns    -9.935uV   596.8uV    -80.69uV
10ns      1.322uV    7.48uV     548.5nV
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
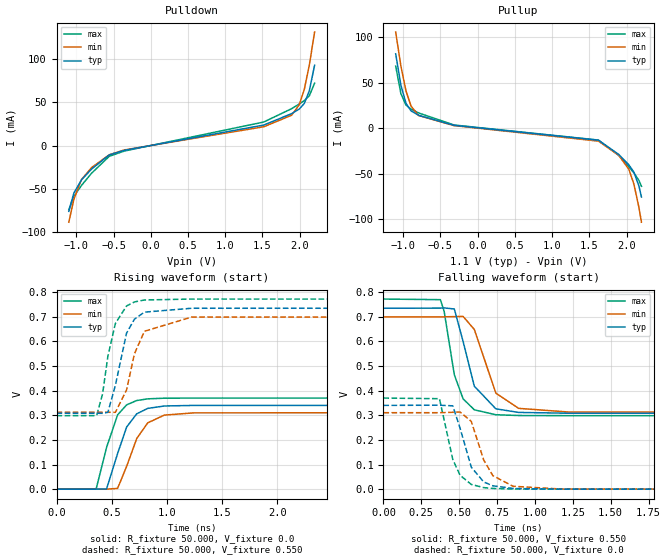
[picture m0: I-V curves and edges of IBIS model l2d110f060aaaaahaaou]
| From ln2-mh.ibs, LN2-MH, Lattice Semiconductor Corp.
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|   Model l2d110f060aaaaahaaou
[Model] l2d110f060aaaaahaaou
Model_type Output
Polarity   Non-Inverting
Enable   Active-High
Vmeas =  0.550V
Cref =  20.000pF
Rref =  50.000
Vref =  0.600V
C_comp   2.000pF   1.500pF   2.500pF
[Temperature Range]   25.000   0.125k   -40.000
[Voltage Range]   1.100V   1.070V   1.130V
[C Comp Corner]
C_comp   2.000pF   1.500pF   2.500pF
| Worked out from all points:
|   slope of the pulldown table from 0 to 0.165 V, typ, clamps not added: 63.7 ohm
|   slope of the pullup table from 0 to 0.165 V, typ, clamps not added: 96.3 ohm
|   rising waveform, R_fixture 50.000, V_fixture 0.0: 20-80 % time 154ps typ, 172ps min, 142ps max; typ from 0 V to 0.34 V
|   rising waveform, R_fixture 50.000, V_fixture 0.550: 20-80 % time 127ps typ, 142ps min, 117ps max; typ from 0.308 V to 0.735 V
|   falling waveform, R_fixture 50.000, V_fixture 0.550: 20-80 % time 108ps typ, 129ps min, 92ps max; typ from 0.735 V to 0.308 V
|   falling waveform, R_fixture 50.000, V_fixture 0.0: 20-80 % time 102ps typ, 118ps min, 87.6ps max; typ from 0.34 V to 0 V
[Pulldown]
|Voltage   I(typ)   I(min)   I(max)
-1.1V     -76.54mA   -89.11mA   -74.6mA
-1.032V   -55.22mA   -62.49mA   -59.02mA
-930mV    -39.93mA   -39.58mA   -46.39mA
-794mV    -27.3mA    -25.59mA   -32.18mA
-556mV    -10.86mA   -10.73mA   -12.48mA
-352mV    -5.545mA   -5.09mA    -6.373mA
1.518V    23.77mA    21.78mA    27.3mA
1.892V    37.04mA    35.19mA    42.81mA
1.994V    42.39mA    47.31mA    48.27mA
2.062V    48.87mA    65.31mA    52.22mA
2.13V     63.83mA    93.74mA    57.88mA
2.2V      93.18mA    131.8mA    72.46mA
[Pullup]
|Voltage   I(typ)   I(min)   I(max)
-1.1V     81.91mA    105.9mA    68.41mA
-1.03V    47.47mA    68.56mA    38.15mA
-962mV    27.53mA    41.2mA     25.58mA
-894mV    19.18mA    24.51mA    21.13mA
-792mV    14.31mA    14.06mA    16.92mA
-316mV    3.287mA    2.986mA    3.66mA
1.622V    -13.09mA   -14.09mA   -12.9mA
1.894V    -28.68mA   -29.62mA   -29.76mA
2.03V     -40.08mA   -44.96mA   -42.32mA
2.098V    -48.2mA    -61.22mA   -49.01mA
2.166V    -63.47mA   -87.06mA   -57.31mA
2.2V      -75.63mA   -103.3mA   -63.79mA
[Ramp]
| variable   typ   min   max
dV/dt_r   0.204/0.154n   0.186/0.172n   0.222/0.142n
dV/dt_f   0.290/0.116n   0.266/0.143n   0.322/97.166p
R_load = 50.000
[Rising Waveform]
R_fixture= 50.000
V_fixture= 0.0
V_fixture_min= 0.0
V_fixture_max= 0.0
|time   V(typ)   V(min)   V(max)
0s        1.483uV    8.334uV    614.8nV
359ps     82.27uV    69.47uV    1.112mV
453ps     892uV      -23.59uV   169.4mV
553ps     144.7mV    3.176mV    301.6mV
635ps     252.5mV    92.66mV    342.4mV
726ps     305.9mV    205.3mV    359.9mV
826ps     328mV      269.3mV    366.7mV
976ps     337.7mV    300.7mV    369.4mV
1.245ns   340.1mV    309.9mV    369.9mV
10ns      340.1mV    310.4mV    369.8mV
[Rising Waveform]
R_fixture= 50.000
V_fixture= 0.550
V_fixture_min= 0.534
V_fixture_max= 0.568
|time   V(typ)   V(min)   V(max)
0s        308.2mV    312.4mV    298.4mV
363ps     308.3mV    312.5mV    298.7mV
417ps     307.9mV    312.5mV    386.5mV
465ps     312.1mV    312.2mV    539.4mV
533ps     421.6mV    311.9mV    672.8mV
634ps     633.5mV    402.9mV    743.9mV
706ps     690.5mV    550.5mV    760.4mV
796ps     718.8mV    641.1mV    768.2mV
1.224ns   734.6mV    698.8mV    771.9mV
10ns      734.6mV    699.4mV    771.8mV
[Falling Waveform]
R_fixture= 50.000
V_fixture= 0.550
V_fixture_min= 0.534
V_fixture_max= 0.568
|time   V(typ)   V(min)   V(max)
0s        734.6mV    699.4mV    771.8mV
376ps     735.1mV    699.4mV    769.4mV
401ps     735.9mV    699.6mV    721.7mV
468ps     731.5mV    700.6mV    464.3mV
526ps     599.4mV    701.3mV    366.8mV
600ps     417.9mV    648.3mV    322.1mV
742ps     326.2mV    389.8mV    302.1mV
892ps     311.5mV    328mV      299mV
1.222ns   308.3mV    313.2mV    298.4mV
10ns      308.2mV    312.4mV    298.4mV
[Falling Waveform]
R_fixture= 50.000
V_fixture= 0.0
V_fixture_min= 0.0
V_fixture_max= 0.0
|time   V(typ)   V(min)   V(max)
0s        340.1mV    310.4mV    369.8mV
370ps     340.9mV    310.4mV    367.3mV
458ps     338.3mV    312.1mV    120.2mV
506ps     247.3mV    313.2mV    56.33mV
580ps     89.14mV    275.1mV    19.12mV
662ps     29.06mV    118.3mV    6.301mV
722ps     13.6mV     54.9mV     2.9mV
856ps     2.845mV    11.61mV    491.3uV
1.172ns   11.57uV    556uV      -75uV
10ns      1.486uV    8.335uV    620.1nV
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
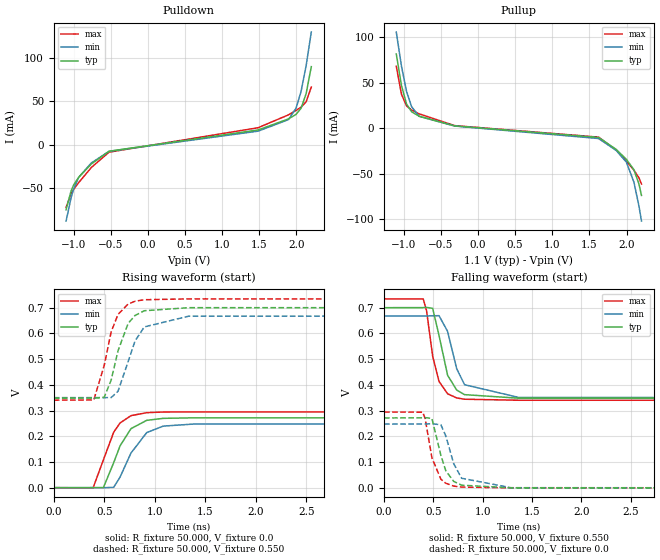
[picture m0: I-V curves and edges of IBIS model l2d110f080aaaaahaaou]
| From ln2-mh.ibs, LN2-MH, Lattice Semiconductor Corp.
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|   Model l2d110f080aaaaahaaou
[Model] l2d110f080aaaaahaaou
Model_type Output
Polarity   Non-Inverting
Enable   Active-High
Vmeas =  0.550V
Cref =  20.000pF
Rref =  50.000
Vref =  0.600V
C_comp   2.000pF   1.500pF   2.500pF
[Temperature Range]   25.000   0.125k   -40.000
[Voltage Range]   1.100V   1.070V   1.130V
[C Comp Corner]
C_comp   2.000pF   1.500pF   2.500pF
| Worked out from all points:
|   slope of the pulldown table from 0 to 0.165 V, typ, clamps not added: 86.1 ohm
|   slope of the pullup table from 0 to 0.165 V, typ, clamps not added: 128 ohm
|   rising waveform, R_fixture 50.000, V_fixture 0.0: 20-80 % time 181ps typ, 207ps min, 171ps max; typ from 0 V to 0.272 V
|   rising waveform, R_fixture 50.000, V_fixture 0.550: 20-80 % time 154ps typ, 175ps min, 145ps max; typ from 0.348 V to 0.7 V
|   falling waveform, R_fixture 50.000, V_fixture 0.550: 20-80 % time 123ps typ, 147ps min, 109ps max; typ from 0.7 V to 0.348 V
|   falling waveform, R_fixture 50.000, V_fixture 0.0: 20-80 % time 114ps typ, 133ps min, 102ps max; typ from 0.272 V to 0 V
[Pulldown]
|Voltage   I(typ)   I(min)   I(max)
-1.1V     -74.9mA    -87.89mA   -72.18mA
-1.032V   -53.02mA   -60.87mA   -56.17mA
-998mV    -46.3mA    -50.95mA   -51.37mA
-930mV    -37.42mA   -37.49mA   -43.53mA
-760mV    -22.08mA   -20.87mA   -26.16mA
-522mV    -7.412mA   -7.551mA   -8.455mA
1.484V    17.14mA    15.77mA    19.72mA
1.892V    29.86mA    29.06mA    34.55mA
1.994V    35.1mA     42.09mA    39.64mA
2.062V    42.16mA    61.38mA    43.43mA
2.13V     58.86mA    91.09mA    49.58mA
2.2V      90.15mA    130.1mA    66.6mA
[Pullup]
|Voltage   I(typ)   I(min)   I(max)
-1.1V     81.52mA    105.6mA    67.94mA
-1.03V    46.8mA     68.07mA    37.3mA
-962mV    26.53mA    40.47mA    24.41mA
-894mV    18mA       23.55mA    19.89mA
-792mV    13.08mA    12.94mA    15.68mA
-316mV    2.48mA     2.28mA     2.753mA
1.622V    -10.23mA   -11.44mA   -9.894mA
1.86V     -23.41mA   -24.54mA   -24.05mA
1.996V    -34.28mA   -37.3mA    -36.36mA
2.098V    -45.67mA   -59.37mA   -46.19mA
2.166V    -61.46mA   -85.7mA    -54.64mA
2.2V      -73.96mA   -102.1mA   -61.39mA
[Ramp]
| variable   typ   min   max
dV/dt_r   0.163/0.181n   0.149/0.207n   0.177/0.171n
dV/dt_f   0.242/0.136n   0.220/0.165n   0.271/0.117n
R_load = 50.000
[Rising Waveform]
R_fixture= 50.000
V_fixture= 0.0
V_fixture_min= 0.0
V_fixture_max= 0.0
|time   V(typ)   V(min)   V(max)
0s        1.706uV    9.484uV    714.8nV
389ps     239.5uV    114uV      -678uV
491ps     315.9uV    -95.92uV   108.2mV
593ps     97.2mV     1.301mV    215.7mV
656ps     162.5mV    41.16mV    251.7mV
764ps     229.6mV    134.5mV    280.1mV
920ps     261.9mV    214.2mV    291.8mV
1.084ns   269.7mV    239.5mV    294.3mV
1.384ns   271.7mV    247.5mV    294.7mV
10ns      271.6mV    247.9mV    294.6mV
[Rising Waveform]
R_fixture= 50.000
V_fixture= 0.550
V_fixture_min= 0.534
V_fixture_max= 0.568
|time   V(typ)   V(min)   V(max)
0s        348.1mV    350.2mV    340.4mV
396ps     348.3mV    350.3mV    341.3mV
499ps     351.6mV    350.1mV    475.4mV
568ps     418.7mV    350.4mV    606.1mV
636ps     532.4mV    375.2mV    673.8mV
736ps     639.1mV    490.3mV    714.5mV
805ps     670mV      571mV      725.2mV
896ps     688.3mV    625.4mV    731.2mV
1.336ns   700.2mV    667.2mV    734.5mV
10ns      700.2mV    667.9mV    734.4mV
[Falling Waveform]
R_fixture= 50.000
V_fixture= 0.550
V_fixture_min= 0.534
V_fixture_max= 0.568
|time   V(typ)   V(min)   V(max)
0s        700.2mV    667.8mV    734.4mV
397ps     700.4mV    667.9mV    734.1mV
431ps     701.3mV    667.9mV    688.2mV
493ps     697.6mV    668.6mV    511.2mV
557ps     592.5mV    669.1mV    413.7mV
644ps     437.6mV    607.9mV    365.5mV
736ps     380mV      463.1mV    349.4mV
816ps     362.2mV    400.8mV    344.4mV
1.366ns   348.3mV    351.2mV    340.4mV
10ns      348.1mV    350.2mV    340.4mV
[Falling Waveform]
R_fixture= 50.000
V_fixture= 0.0
V_fixture_min= 0.0
V_fixture_max= 0.0
|time   V(typ)   V(min)   V(max)
0s        271.6mV    247.9mV    294.6mV
393ps     272.1mV    248mV      294mV
418ps     272.8mV    248.1mV    266.6mV
485ps     269.8mV    249.1mV    117.2mV
576ps     126.3mV    245.2mV    33.43mV
626ps     66.1mV     201.5mV    17.7mV
706ps     25.03mV    93.82mV    6.888mV
786ps     10.3mV     37.31mV    2.914mV
1.286ns   99.49uV    559uV      -23.67uV
10ns      1.705uV    9.477uV    719nV
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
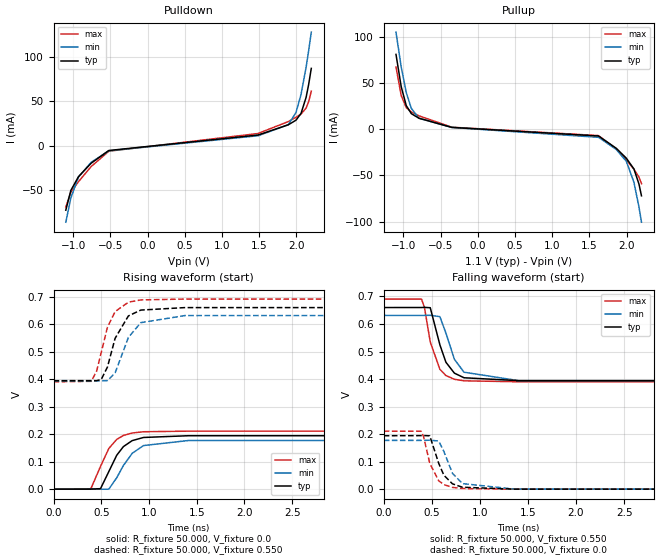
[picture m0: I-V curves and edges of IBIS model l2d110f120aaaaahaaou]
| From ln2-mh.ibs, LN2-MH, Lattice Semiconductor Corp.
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|   Model l2d110f120aaaaahaaou
[Model] l2d110f120aaaaahaaou
Model_type Output
Polarity   Non-Inverting
Enable   Active-High
Vmeas =  0.550V
Cref =  20.000pF
Rref =  50.000
Vref =  0.600V
C_comp   2.000pF   1.500pF   2.500pF
[Temperature Range]   25.000   0.125k   -40.000
[Voltage Range]   1.100V   1.070V   1.130V
[C Comp Corner]
C_comp   2.000pF   1.500pF   2.500pF
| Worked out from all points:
|   slope of the pulldown table from 0 to 0.165 V, typ, clamps not added: 126 ohm
|   slope of the pullup table from 0 to 0.165 V, typ, clamps not added: 191 ohm
|   rising waveform, R_fixture 50.000, V_fixture 0.0: 20-80 % time 186ps typ, 208ps min, 177ps max; typ from 0 V to 0.194 V
|   rising waveform, R_fixture 50.000, V_fixture 0.550: 20-80 % time 156ps typ, 174ps min, 147ps max; typ from 0.394 V to 0.66 V
|   falling waveform, R_fixture 50.000, V_fixture 0.550: 20-80 % time 135ps typ, 155ps min, 121ps max; typ from 0.66 V to 0.394 V
|   falling waveform, R_fixture 50.000, V_fixture 0.0: 20-80 % time 126ps typ, 141ps min, 115ps max; typ from 0.194 V to 0 V
[Pulldown]
|Voltage   I(typ)   I(min)   I(max)
-1.1V     -72.72mA   -86.23mA   -69.18mA
-1.032V   -50.49mA   -58.98mA   -52.58mA
-930mV    -35.09mA   -35.5mA    -40.7mA
-760mV    -19.94mA   -18.95mA   -23.73mA
-522mV    -5.596mA   -5.943mA   -6.368mA
1.484V    11.8mA     10.98mA    13.51mA
1.892V    23.36mA    23.46mA    27.01mA
1.994V    28.49mA    37.15mA    31.75mA
2.062V    36.06mA    57.37mA    35.42mA
2.13V     54.1mA     87.94mA    42.07mA
2.164V    68.38mA    106.4mA    49.14mA
2.2V      86.75mA    127.6mA    61.15mA
[Pullup]
|Voltage   I(typ)   I(min)   I(max)
-1.1V     80.97mA    105.1mA    67.38mA
-1.03V    46.03mA    67.42mA    36.42mA
-962mV    25.5mA     39.64mA    23.27mA
-894mV    16.82mA    22.55mA    18.69mA
-792mV    11.87mA    11.82mA    14.46mA
-350mV    1.926mA    1.847mA    2.152mA
1.622V    -7.397mA   -8.8mA     -6.95mA
1.86V     -20.65mA   -21.86mA   -21.27mA
1.996V    -31.38mA   -34.74mA   -33.39mA
2.098V    -43mA      -57.38mA   -43.23mA
2.166V    -59.35mA   -84.12mA   -51.95mA
2.2V      -72.16mA   -100.7mA   -59.01mA
[Ramp]
| variable   typ   min   max
dV/dt_r   0.117/0.186n   0.106/0.209n   0.126/0.177n
dV/dt_f   0.187/0.147n   0.168/0.174n   0.212/0.130n
R_load = 50.000
[Rising Waveform]
R_fixture= 50.000
V_fixture= 0.0
V_fixture_min= 0.0
V_fixture_max= 0.0
|time   V(typ)   V(min)   V(max)
0s        1.968uV    10.82uV    835.4nV
390ps     257.9uV    127.3uV    743.8uV
492ps     1.822mV    -14.57uV   82.58mV
579ps     63.88mV    25.54uV    147.7mV
662ps     123.3mV    41.54mV    180.9mV
732ps     154.7mV    86.13mV    195.1mV
824ps     176.4mV    130.2mV    204.1mV
942ps     187.8mV    158.4mV    208.6mV
1.414ns   194.2mV    176.8mV    210.8mV
10ns      194.2mV    177.2mV    210.7mV
[Rising Waveform]
R_fixture= 50.000
V_fixture= 0.550
V_fixture_min= 0.534
V_fixture_max= 0.568
|time   V(typ)   V(min)   V(max)
0s        394.1mV    393.4mV    390mV
396ps     394.2mV    393.5mV    391.9mV
452ps     394.1mV    393.6mV    429.5mV
500ps     398.7mV    393.3mV    497.3mV
565ps     444mV      394.3mV    588.9mV
645ps     548.2mV    422.2mV    645.1mV
784ps     629.4mV    551.4mV    679.4mV
914ps     650.7mV    605mV      687.6mV
1.376ns   659.7mV    630.7mV    690.7mV
10ns      659.8mV    631.2mV    690.6mV
[Falling Waveform]
R_fixture= 50.000
V_fixture= 0.550
V_fixture_min= 0.534
V_fixture_max= 0.568
|time   V(typ)   V(min)   V(max)
0s        659.8mV    631.2mV    690.6mV
393ps     659.9mV    631.2mV    690.5mV
424ps     660.4mV    631.2mV    659.5mV
484ps     659.1mV    631.7mV    534.6mV
584ps     524.5mV    626.8mV    435.5mV
647ps     460.9mV    566.7mV    412.8mV
735ps     421.5mV    471.8mV    399.2mV
835ps     404.7mV    424.9mV    393.6mV
1.404ns   394.2mV    394.1mV    390.1mV
10ns      394.1mV    393.4mV    390mV
[Falling Waveform]
R_fixture= 50.000
V_fixture= 0.0
V_fixture_min= 0.0
V_fixture_max= 0.0
|time   V(typ)   V(min)   V(max)
0s        194.2mV    177.2mV    210.7mV
390ps     194.5mV    177.2mV    210.4mV
414ps     194.9mV    177.2mV    191.6mV
479ps     193.7mV    177.9mV    93.88mV
572ps     93.71mV    174.9mV    30.38mV
626ps     50.43mV    136.6mV    16.46mV
715ps     19.41mV    57.49mV    6.404mV
819ps     6.977mV    20.14mV    2.385mV
1.357ns   149uV      438.8uV    33.42uV
10ns      1.966uV    10.81uV    838.4nV
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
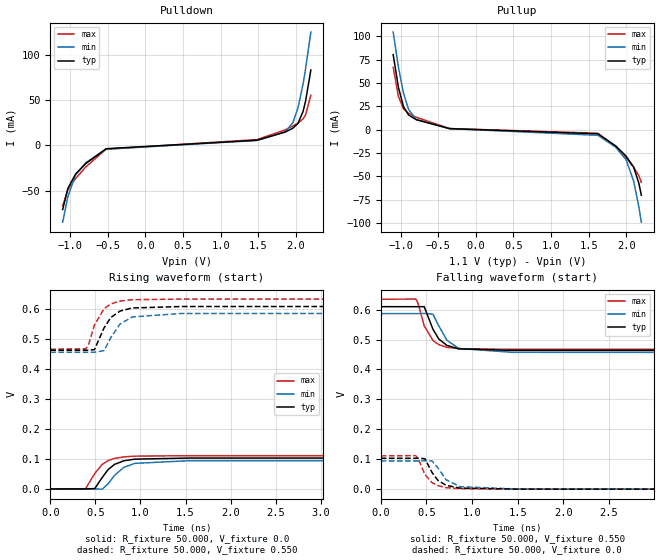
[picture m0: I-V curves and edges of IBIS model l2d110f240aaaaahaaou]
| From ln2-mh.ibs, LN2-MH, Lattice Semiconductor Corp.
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|   Model l2d110f240aaaaahaaou
[Model] l2d110f240aaaaahaaou
Model_type Output
Polarity   Non-Inverting
Enable   Active-High
Vmeas =  0.550V
Cref =  20.000pF
Rref =  50.000
Vref =  0.600V
C_comp   2.000pF   1.500pF   2.500pF
[Temperature Range]   25.000   0.125k   -40.000
[Voltage Range]   1.100V   1.070V   1.130V
[C Comp Corner]
C_comp   2.000pF   1.500pF   2.500pF
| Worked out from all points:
|   slope of the pulldown table from 0 to 0.165 V, typ, clamps not added: 267 ohm
|   slope of the pullup table from 0 to 0.165 V, typ, clamps not added: 387 ohm
|   rising waveform, R_fixture 50.000, V_fixture 0.0: 20-80 % time 174ps typ, 192ps min, 166ps max; typ from 0 V to 0.103 V
|   rising waveform, R_fixture 50.000, V_fixture 0.550: 20-80 % time 160ps typ, 175ps min, 151ps max; typ from 0.463 V to 0.61 V
|   falling waveform, R_fixture 50.000, V_fixture 0.550: 20-80 % time 146ps typ, 161ps min, 135ps max; typ from 0.61 V to 0.463 V
|   falling waveform, R_fixture 50.000, V_fixture 0.0: 20-80 % time 142ps typ, 154ps min, 133ps max; typ from 0.103 V to 0 V
[Pulldown]
|Voltage   I(typ)   I(min)   I(max)
-1.1V     -70.48mA   -84.41mA   -66.47mA
-1.032V   -47.45mA   -56.65mA   -49mA
-930mV    -31.54mA   -32.58mA   -36.61mA
-794mV    -19.97mA   -19.02mA   -23.71mA
-522mV    -3.537mA   -4.129mA   -4.009mA
1.484V    5.747mA    5.596mA    6.505mA
1.858V    14.78mA    15mA       17.13mA
1.96V     18.95mA    25mA       21.38mA
2.028V    24.23mA    40.98mA    24.5mA
2.096V    37.34mA    67.59mA    29.2mA
2.13V     48.92mA    84.48mA    33.88mA
2.2V      83.05mA    124.8mA    55.4mA
[Pullup]
|Voltage   I(typ)   I(min)   I(max)
-1.1V     80.41mA    104.6mA    66.79mA
-1.03V    45.25mA    66.76mA    35.51mA
-962mV    24.45mA    38.8mA     22.09mA
-894mV    15.63mA    21.53mA    17.44mA
-792mV    10.64mA    10.68mA    13.21mA
-350mV    1.031mA    1.067mA    1.152mA
1.622V    -4.519mA   -6.12mA    -3.927mA
1.86V     -17.57mA   -18.98mA   -18.12mA
1.996V    -28.35mA   -32.13mA   -30.22mA
2.098V    -40.35mA   -55.36mA   -40.27mA
2.166V    -57.26mA   -82.54mA   -49.29mA
2.2V      -70.38mA   -99.32mA   -56.65mA
[Ramp]
| variable   typ   min   max
dV/dt_r   61.964m/0.174n   56.610m/0.192n   66.720m/0.166n
dV/dt_f   0.104/0.153n   92.369m/0.173n   0.120/0.140n
R_load = 50.000
[Rising Waveform]
R_fixture= 50.000
V_fixture= 0.0
V_fixture_min= 0.0
V_fixture_max= 0.0
|time   V(typ)   V(min)   V(max)
0s        2.356uV    12.75uV    1.02uV
389ps     296.8uV    144uV      -127.8uV
493ps     1.233mV    27.24uV    51.46mV
576ps     38.3mV     -622.4uV   82.12mV
643ps     65.4mV     17.81mV    94.98mV
713ps     82.16mV    45.72mV    102.3mV
815ps     94.12mV    71.95mV    107.3mV
935ps     99.67mV    85.46mV    109.7mV
1.514ns   103.2mV    94.1mV     111.2mV
10ns      103.3mV    94.36mV    111.2mV
[Rising Waveform]
R_fixture= 50.000
V_fixture= 0.550
V_fixture_min= 0.534
V_fixture_max= 0.568
|time   V(typ)   V(min)   V(max)
0s        463.4mV    456.7mV    467.1mV
394ps     463.6mV    456.8mV    468.3mV
424ps     463.5mV    456.9mV    481.9mV
490ps     465.5mV    456.7mV    547.8mV
597ps     538.5mV    462.4mV    602.4mV
672ps     572.9mV    506.2mV    618.3mV
774ps     594.5mV    551.3mV    627.9mV
912ps     604.8mV    575mV      632.4mV
1.452ns   609.6mV    586.3mV    634.5mV
10ns      609.7mV    586.7mV    634.5mV
[Falling Waveform]
R_fixture= 50.000
V_fixture= 0.550
V_fixture_min= 0.534
V_fixture_max= 0.568
|time   V(typ)   V(min)   V(max)
0s        609.7mV    586.6mV    634.5mV
384ps     609.6mV    586.6mV    635.1mV
405ps     609.8mV    586.6mV    623.7mV
476ps     609.6mV    586.8mV    545.7mV
572ps     534mV      584.7mV    496.6mV
636ps     501.6mV    545.2mV    482.8mV
725ps     480.2mV    497.1mV    473.8mV
855ps     468.8mV    470.1mV    469.3mV
1.445ns   463.6mV    457.1mV    467.2mV
10ns      463.4mV    456.7mV    467.1mV
[Falling Waveform]
R_fixture= 50.000
V_fixture= 0.0
V_fixture_min= 0.0
V_fixture_max= 0.0
|time   V(typ)   V(min)   V(max)
0s        103.3mV    94.36mV    111.2mV
383ps     103.3mV    94.31mV    112.1mV
411ps     103.6mV    94.35mV    101.2mV
484ps     101.6mV    94.78mV    48.6mV
561ps     56.06mV    94.41mV    22.04mV
626ps     29.43mV    71.27mV    11.68mV
715ps     12.86mV    31.63mV    5.105mV
867ps     3.506mV    8.451mV    1.478mV
1.495ns   199.1uV    298.4uV    149.2uV
10ns      2.355uV    12.73uV    1.02uV
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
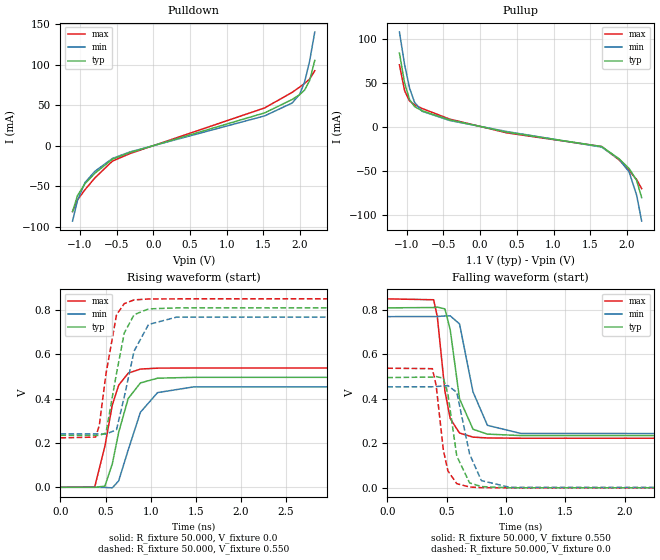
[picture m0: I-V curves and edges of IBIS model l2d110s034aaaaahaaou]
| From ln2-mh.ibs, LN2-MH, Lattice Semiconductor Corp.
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|   Model l2d110s034aaaaahaaou
[Model] l2d110s034aaaaahaaou
Model_type Output
Polarity   Non-Inverting
Enable   Active-High
Vmeas =  0.550V
Cref =  20.000pF
Rref =  50.000
Vref =  0.600V
C_comp   2.000pF   1.500pF   2.500pF
[Temperature Range]   25.000   0.125k   -40.000
[Voltage Range]   1.100V   1.070V   1.130V
[C Comp Corner]
C_comp   2.000pF   1.500pF   2.500pF
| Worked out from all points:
|   slope of the pulldown table from 0 to 0.165 V, typ, clamps not added: 37.1 ohm
|   slope of the pullup table from 0 to 0.165 V, typ, clamps not added: 55.5 ohm
|   rising waveform, R_fixture 50.000, V_fixture 0.0: 20-80 % time 176ps typ, 220ps min, 157ps max; typ from 0 V to 0.496 V
|   rising waveform, R_fixture 50.000, V_fixture 0.550: 20-80 % time 145ps typ, 182ps min, 128ps max; typ from 0.234 V to 0.809 V
|   falling waveform, R_fixture 50.000, V_fixture 0.550: 20-80 % time 95.8ps typ, 122ps min, 80.8ps max; typ from 0.809 V to 0.234 V
|   falling waveform, R_fixture 50.000, V_fixture 0.0: 20-80 % time 87.3ps typ, 107ps min, 75.5ps max; typ from 0.496 V to 0 V
[Pulldown]
|Voltage   I(typ)   I(min)   I(max)
-1.1V     -81.59mA   -93.17mA   -81.22mA
-1.032V   -61.62mA   -67.46mA   -66.97mA
-930mV    -46.97mA   -45.58mA   -54.42mA
-794mV    -34.04mA   -31.61mA   -39.78mA
-556mV    -16.66mA   -15.87mA   -19.1mA
-318mV    -8.586mA   -7.811mA   -9.863mA
1.518V    40.44mA    36.73mA    46.57mA
1.892V    56.98mA    52.59mA    65.78mA
1.994V    62.92mA    63.32mA    72.3mA
2.062V    68.66mA    78.75mA    76.84mA
2.13V     80.38mA    104.4mA    82.16mA
2.2V      105.2mA    140.3mA    92.49mA
[Pullup]
|Voltage   I(typ)   I(min)   I(max)
-1.1V     83.6mA     107.5mA    70.17mA
-1.03V    49.84mA    70.54mA    40.88mA
-962mV    30.67mA    43.73mA    29.06mA
-894mV    22.74mA    27.56mA    24.79mA
-792mV    17.97mA    17.43mA    20.61mA
-418mV    7.65mA     6.925mA    8.54mA
364mV     -6.384mA   -5.65mA    -7.161mA
1.656V    -22.72mA   -23.35mA   -22.74mA
1.894V    -36.76mA   -37.21mA   -37.99mA
2.03V     -47.82mA   -51.73mA   -50.2mA
2.132V    -61.22mA   -78.08mA   -60.36mA
2.2V      -80.8mA    -107.4mA   -70.51mA
[Ramp]
| variable   typ   min   max
dV/dt_r   0.297/0.176n   0.272/0.220n   0.323/0.157n
dV/dt_f   0.379/0.105n   0.352/0.137n   0.412/86.403p
R_load = 50.000
[Rising Waveform]
R_fixture= 50.000
V_fixture= 0.0
V_fixture_min= 0.0
V_fixture_max= 0.0
|time   V(typ)   V(min)   V(max)
0s        1.065uV    6.127uV    432.2nV
380ps     24.9uV     55.5uV     1.639mV
492ps     5.23mV     -759.1uV   184.4mV
575ps     106.2mV    -2.443mV   371.4mV
645ps     247.7mV    29.02mV    460.1mV
751ps     400.3mV    168.6mV    514.5mV
886ps     470.3mV    338.2mV    532.7mV
1.076ns   491.7mV    426.7mV    537mV
1.476ns   495.5mV    452.5mV    537.6mV
10ns      495.6mV    454mV      537.6mV
[Rising Waveform]
R_fixture= 50.000
V_fixture= 0.550
V_fixture_min= 0.534
V_fixture_max= 0.568
|time   V(typ)   V(min)   V(max)
0s        234.3mV    240.5mV    222.8mV
390ps     234.2mV    240.6mV    226.4mV
430ps     233.5mV    240.6mV    278.1mV
504ps     244.8mV    239.7mV    509.8mV
621ps     512.9mV    259.4mV    776.8mV
707ps     695.1mV    407.2mV    827.7mV
816ps     777.8mV    613.8mV    844.4mV
976ps     803.8mV    733.6mV    848.6mV
1.286ns   808.6mV    766.7mV    849.1mV
10ns      808.7mV    769.4mV    849.1mV
[Falling Waveform]
R_fixture= 50.000
V_fixture= 0.550
V_fixture_min= 0.534
V_fixture_max= 0.568
|time   V(typ)   V(min)   V(max)
0s        808.7mV    769.4mV    849.1mV
390ps     810.2mV    769.6mV    845.1mV
421ps     812mV      770mV      769.7mV
485ps     804.2mV    772.2mV    435mV
530ps     709.6mV    772.8mV    311mV
608ps     400.4mV    736.6mV    246.3mV
722ps     263.3mV    430.6mV    227.9mV
843ps     241.4mV    281mV      224.2mV
1.122ns   235mV      244.6mV    222.9mV
10ns      234.3mV    240.5mV    222.8mV
[Falling Waveform]
R_fixture= 50.000
V_fixture= 0.0
V_fixture_min= 0.0
V_fixture_max= 0.0
|time   V(typ)   V(min)   V(max)
0s        495.5mV    454mV      537.5mV
379ps     497.7mV    454.1mV    535.5mV
411ps     500.1mV    454.9mV    461.3mV
472ps     492.7mV    457.9mV    169.4mV
510ps     421.9mV    459.4mV    76.42mV
585ps     142.7mV    429.3mV    18.81mV
693ps     22.2mV     151.6mV    3.651mV
792ps     5.73mV     32.69mV    933.4uV
1.032ns   342.2uV    2.337mV    -4.665uV
10ns      1.066uV    6.117uV    438nV
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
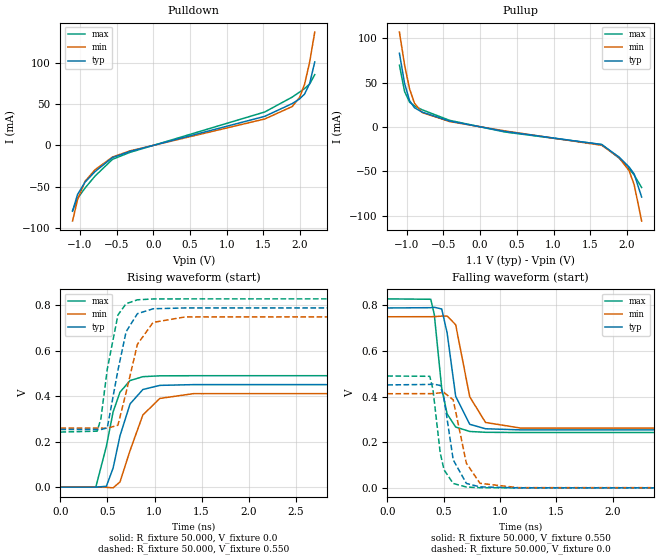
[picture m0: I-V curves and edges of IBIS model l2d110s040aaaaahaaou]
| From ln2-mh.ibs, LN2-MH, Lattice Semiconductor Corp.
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|   Model l2d110s040aaaaahaaou
[Model] l2d110s040aaaaahaaou
Model_type Output
Polarity   Non-Inverting
Enable   Active-High
Vmeas =  0.550V
Cref =  20.000pF
Rref =  50.000
Vref =  0.600V
C_comp   2.000pF   1.500pF   2.500pF
[Temperature Range]   25.000   0.125k   -40.000
[Voltage Range]   1.100V   1.070V   1.130V
[C Comp Corner]
C_comp   2.000pF   1.500pF   2.500pF
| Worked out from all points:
|   slope of the pulldown table from 0 to 0.165 V, typ, clamps not added: 42.8 ohm
|   slope of the pullup table from 0 to 0.165 V, typ, clamps not added: 64.5 ohm
|   rising waveform, R_fixture 50.000, V_fixture 0.0: 20-80 % time 170ps typ, 207ps min, 154ps max; typ from 0 V to 0.451 V
|   rising waveform, R_fixture 50.000, V_fixture 0.550: 20-80 % time 140ps typ, 171ps min, 125ps max; typ from 0.254 V to 0.788 V
|   falling waveform, R_fixture 50.000, V_fixture 0.550: 20-80 % time 97.3ps typ, 121ps min, 82.5ps max; typ from 0.788 V to 0.254 V
|   falling waveform, R_fixture 50.000, V_fixture 0.0: 20-80 % time 89.6ps typ, 107ps min, 77.7ps max; typ from 0.451 V to 0 V
[Pulldown]
|Voltage   I(typ)   I(min)   I(max)
-1.1V     -79.96mA   -91.87mA   -79.09mA
-1.032V   -59.57mA   -65.87mA   -64.43mA
-930mV    -44.73mA   -43.66mA   -51.86mA
-794mV    -31.89mA   -29.69mA   -37.36mA
-556mV    -14.81mA   -14.23mA   -16.99mA
-318mV    -7.449mA   -6.777mA   -8.559mA
1.518V    35.14mA    31.97mA    40.44mA
1.892V    50.64mA    47.02mA    58.47mA
1.994V    56.37mA    58.13mA    64.65mA
2.062V    62.28mA    74.36mA    68.99mA
2.13V     74.93mA    100.9mA    74.33mA
2.2V      101.2mA    137.5mA    85.79mA
[Pullup]
|Voltage   I(typ)   I(min)   I(max)
-1.1V     83.04mA    107mA      69.59mA
-1.03V    49.05mA    69.88mA    39.98mA
-962mV    29.63mA    42.86mA    27.91mA
-894mV    21.56mA    26.55mA    23.58mA
-792mV    16.75mA    16.31mA    19.39mA
-418mV    6.661mA    6.061mA    7.463mA
330mV     -5.014mA   -4.428mA   -5.641mA
1.656V    -19.9mA    -20.72mA   -19.81mA
1.894V    -34.07mA   -34.69mA   -35.26mA
2.03V     -45.27mA   -49.5mA    -47.61mA
2.098V    -53.07mA   -65.07mA   -54.23mA
2.2V      -79.11mA   -106.1mA   -68.33mA
[Ramp]
| variable   typ   min   max
dV/dt_r   0.271/0.171n   0.247/0.207n   0.294/0.154n
dV/dt_f   0.355/0.106n   0.330/0.137n   0.389/87.794p
R_load = 50.000
[Rising Waveform]
R_fixture= 50.000
V_fixture= 0.0
V_fixture_min= 0.0
V_fixture_max= 0.0
|time   V(typ)   V(min)   V(max)
0s        1.175uV    6.716uV    479.8nV
376ps     53.07uV    57.76uV    419.3uV
488ps     3.873mV    -611.8uV   179.3mV
560ps     84.34mV    -2.987mV   331.3mV
633ps     226mV      23.12mV    417.8mV
740ps     366.1mV    161.2mV    468.7mV
876ps     429.2mV    317.2mV    485.7mV
1.056ns   447.5mV    390.1mV    489.5mV
1.416ns   450.8mV    411.2mV    490mV
10ns      450.8mV    412.4mV    490mV
[Rising Waveform]
R_fixture= 50.000
V_fixture= 0.550
V_fixture_min= 0.534
V_fixture_max= 0.568
|time   V(typ)   V(min)   V(max)
0s        253.6mV    259.5mV    242.3mV
390ps     253.5mV    259.6mV    246.2mV
430ps     252.9mV    259.6mV    300.7mV
498ps     260.9mV    258.8mV    519.3mV
611ps     514mV      272.6mV    757mV
698ps     683.5mV    416.4mV    806.5mV
818ps     762.6mV    627.9mV    823.7mV
985ps     784.3mV    724.4mV    827.4mV
1.325ns   787.9mV    748.3mV    827.8mV
10ns      787.9mV    749.4mV    827.8mV
[Falling Waveform]
R_fixture= 50.000
V_fixture= 0.550
V_fixture_min= 0.534
V_fixture_max= 0.568
|time   V(typ)   V(min)   V(max)
0s        787.9mV    749.4mV    827.8mV
386ps     789.2mV    749.6mV    826mV
417ps     790.9mV    750mV      759.3mV
483ps     783.6mV    752.1mV    436.4mV
531ps     678.7mV    752.6mV    323.6mV
607ps     400.9mV    714.6mV    266.3mV
732ps     278.3mV    398.7mV    246.9mV
872ps     258.8mV    286.4mV    243.3mV
1.183ns   253.9mV    261.9mV    242.3mV
10ns      253.6mV    259.5mV    242.3mV
[Falling Waveform]
R_fixture= 50.000
V_fixture= 0.0
V_fixture_min= 0.0
V_fixture_max= 0.0
|time   V(typ)   V(min)   V(max)
0s        450.8mV    412.4mV    489.9mV
377ps     452.9mV    412.5mV    488.6mV
405ps     454.9mV    413.1mV    431.7mV
470ps     448.6mV    416.2mV    152mV
504ps     390.8mV    417.6mV    78.54mV
585ps     122.7mV    385.6mV    19.13mV
702ps     19.31mV    107.8mV    3.473mV
823ps     4.112mV    19.73mV    659.8uV
1.162ns   23.69uV    763.1uV    -56.29uV
10ns      1.177uV    6.709uV    485.5nV
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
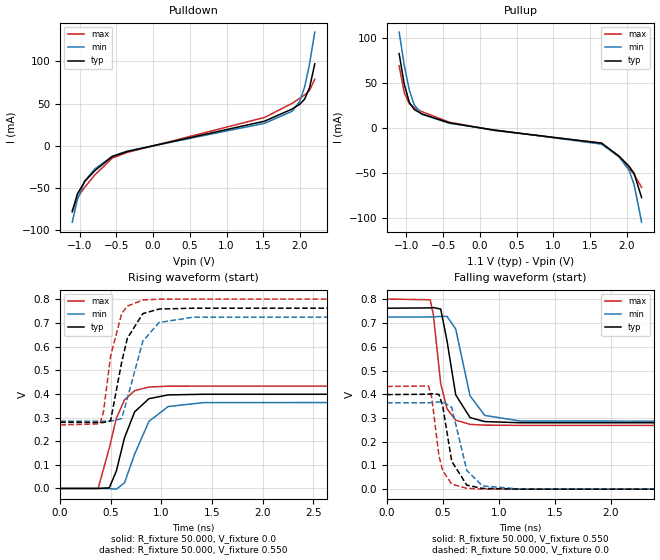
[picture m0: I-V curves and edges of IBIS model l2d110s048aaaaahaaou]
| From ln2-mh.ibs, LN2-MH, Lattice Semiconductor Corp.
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|   Model l2d110s048aaaaahaaou
[Model] l2d110s048aaaaahaaou
Model_type Output
Polarity   Non-Inverting
Enable   Active-High
Vmeas =  0.550V
Cref =  20.000pF
Rref =  50.000
Vref =  0.600V
C_comp   2.000pF   1.500pF   2.500pF
[Temperature Range]   25.000   0.125k   -40.000
[Voltage Range]   1.100V   1.070V   1.130V
[C Comp Corner]
C_comp   2.000pF   1.500pF   2.500pF
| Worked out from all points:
|   slope of the pulldown table from 0 to 0.165 V, typ, clamps not added: 51.7 ohm
|   slope of the pullup table from 0 to 0.165 V, typ, clamps not added: 77.4 ohm
|   rising waveform, R_fixture 50.000, V_fixture 0.0: 20-80 % time 170ps typ, 207ps min, 151ps max; typ from 0 V to 0.399 V
|   rising waveform, R_fixture 50.000, V_fixture 0.550: 20-80 % time 140ps typ, 173ps min, 122ps max; typ from 0.28 V to 0.763 V
|   falling waveform, R_fixture 50.000, V_fixture 0.550: 20-80 % time 103ps typ, 128ps min, 86.7ps max; typ from 0.763 V to 0.28 V
|   falling waveform, R_fixture 50.000, V_fixture 0.0: 20-80 % time 94.1ps typ, 111ps min, 81ps max; typ from 0.399 V to 0 V
[Pulldown]
|Voltage   I(typ)   I(min)   I(max)
-1.1V     -78.14mA   -90.41mA   -76.7mA
-1.032V   -57.25mA   -64.07mA   -61.57mA
-930mV    -42.18mA   -41.5mA    -48.97mA
-794mV    -29.46mA   -27.52mA   -34.62mA
-556mV    -12.72mA   -12.38mA   -14.61mA
-352mV    -6.823mA   -6.248mA   -7.842mA
1.518V    29.15mA    26.61mA    33.53mA
1.892V    43.47mA    40.78mA    50.24mA
1.994V    48.99mA    52.39mA    56.03mA
2.062V    55.16mA    69.53mA    60.16mA
2.13V     68.97mA    97.07mA    65.62mA
2.2V      96.87mA    134.5mA    78.6mA
[Pullup]
|Voltage   I(typ)   I(min)   I(max)
-1.1V     82.47mA    106.4mA    68.98mA
-1.03V    48.25mA    69.21mA    39.04mA
-962mV    28.56mA    42.03mA    26.72mA
-894mV    20.36mA    25.52mA    22.34mA
-792mV    15.52mA    15.17mA    18.14mA
-418mV    5.653mA    5.18mA     6.352mA
194mV     -2.501mA   -2.203mA   -2.816mA
1.656V    -17.03mA   -18.06mA   -16.81mA
1.894V    -31.36mA   -32.15mA   -32.48mA
2.03V     -42.69mA   -47.23mA   -44.96mA
2.098V    -50.65mA   -63.14mA   -51.63mA
2.2V      -77.38mA   -104.7mA   -66.08mA
[Ramp]
| variable   typ   min   max
dV/dt_r   0.239/0.170n   0.219/0.207n   0.260/0.152n
dV/dt_f   0.324/0.113n   0.299/0.146n   0.357/92.770p
R_load = 50.000
[Rising Waveform]
R_fixture= 50.000
V_fixture= 0.0
V_fixture_min= 0.0
V_fixture_max= 0.0
|time   V(typ)   V(min)   V(max)
0s        1.321uV    7.484uV    543nV
375ps     65.31uV    64.28uV    13.91uV
485ps     2.586mV    -535.2uV   171.2mV
555ps     74.32mV    -2.97mV    297.7mV
635ps     214.8mV    23.84mV    375mV
735ps     324.2mV    145.3mV    414mV
876ps     380mV      283.8mV    429.4mV
1.066ns   396mV      346.9mV    432.8mV
1.416ns   398.7mV    363.4mV    433.2mV
10ns      398.7mV    364.3mV    433.1mV
[Rising Waveform]
R_fixture= 50.000
V_fixture= 0.550
V_fixture_min= 0.534
V_fixture_max= 0.568
|time   V(typ)   V(min)   V(max)
0s        279.8mV    284.9mV    268.9mV
392ps     279.6mV    285mV      273.6mV
427ps     279.1mV    285mV      322.7mV
498ps     286.9mV    284.2mV    561.3mV
607ps     533.9mV    296.1mV    740mV
663ps     635.6mV    380.8mV    771.8mV
816ps     740.1mV    623.4mV    797.6mV
976ps     759.3mV    702.4mV    801.2mV
1.316ns   763mV      724.9mV    801.6mV
10ns      763mV      726mV      801.6mV
[Falling Waveform]
R_fixture= 50.000
V_fixture= 0.550
V_fixture_min= 0.534
V_fixture_max= 0.568
|time   V(typ)   V(min)   V(max)
0s        763mV      725.9mV    801.6mV
386ps     764.3mV    726.1mV    798.7mV
414ps     765.8mV    726.5mV    736.2mV
480ps     759.5mV    728.4mV    444.5mV
536ps     626mV      728.7mV    338.9mV
614ps     397.5mV    675.2mV    290.9mV
742ps     301.7mV    393.7mV    273.2mV
873ps     285mV      311mV      269.8mV
1.192ns   280mV      287.1mV    268.9mV
10ns      279.8mV    284.9mV    268.9mV
[Falling Waveform]
R_fixture= 50.000
V_fixture= 0.0
V_fixture_min= 0.0
V_fixture_max= 0.0
|time   V(typ)   V(min)   V(max)
0s        398.7mV    364.3mV    433.1mV
371ps     400.3mV    364.3mV    435mV
400ps     402.3mV    364.9mV    386.5mV
464ps     399.4mV    367.6mV    140.9mV
497ps     352.8mV    369.1mV    78.67mV
578ps     117.7mV    345.1mV    21.43mV
713ps     16.77mV    78.78mV    3.36mV
853ps     3.21mV     13.67mV    523.9uV
1.182ns   12.73uV    714.5uV    -72.81uV
10ns      1.323uV    7.48uV     548.3nV
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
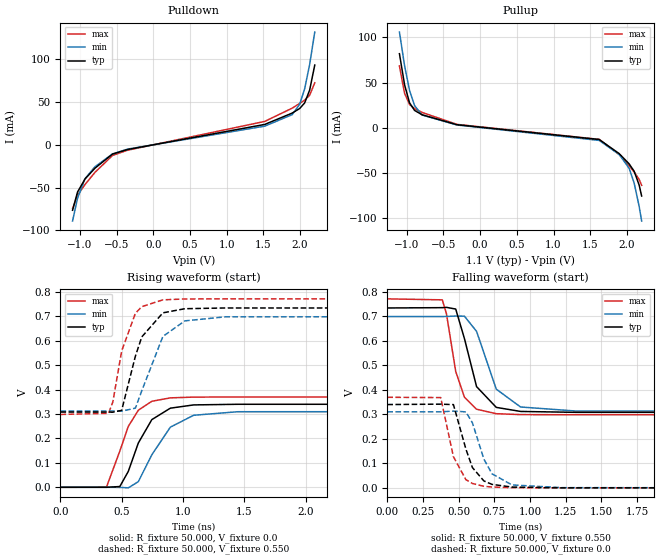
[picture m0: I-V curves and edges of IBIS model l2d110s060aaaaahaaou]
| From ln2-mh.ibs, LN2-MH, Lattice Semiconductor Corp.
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|   Model l2d110s060aaaaahaaou
[Model] l2d110s060aaaaahaaou
Model_type Output
Polarity   Non-Inverting
Enable   Active-High
Vmeas =  0.550V
Cref =  20.000pF
Rref =  50.000
Vref =  0.600V
C_comp   2.000pF   1.500pF   2.500pF
[Temperature Range]   25.000   0.125k   -40.000
[Voltage Range]   1.100V   1.070V   1.130V
[C Comp Corner]
C_comp   2.000pF   1.500pF   2.500pF
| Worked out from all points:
|   slope of the pulldown table from 0 to 0.165 V, typ, clamps not added: 63.7 ohm
|   slope of the pullup table from 0 to 0.165 V, typ, clamps not added: 96.3 ohm
|   rising waveform, R_fixture 50.000, V_fixture 0.0: 20-80 % time 181ps typ, 221ps min, 160ps max; typ from 0 V to 0.34 V
|   rising waveform, R_fixture 50.000, V_fixture 0.550: 20-80 % time 148ps typ, 181ps min, 129ps max; typ from 0.308 V to 0.735 V
|   falling waveform, R_fixture 50.000, V_fixture 0.550: 20-80 % time 115ps typ, 143ps min, 97.2ps max; typ from 0.735 V to 0.308 V
|   falling waveform, R_fixture 50.000, V_fixture 0.0: 20-80 % time 104ps typ, 121ps min, 89.5ps max; typ from 0.34 V to 0 V
[Pulldown]
|Voltage   I(typ)   I(min)   I(max)
-1.1V     -76.54mA   -89.11mA   -74.6mA
-1.032V   -55.22mA   -62.49mA   -59.02mA
-930mV    -39.93mA   -39.58mA   -46.39mA
-794mV    -27.3mA    -25.59mA   -32.18mA
-556mV    -10.86mA   -10.73mA   -12.48mA
-352mV    -5.545mA   -5.09mA    -6.373mA
1.518V    23.77mA    21.78mA    27.3mA
1.892V    37.04mA    35.19mA    42.81mA
1.994V    42.39mA    47.31mA    48.27mA
2.062V    48.87mA    65.31mA    52.22mA
2.13V     63.83mA    93.74mA    57.88mA
2.2V      93.18mA    131.8mA    72.46mA
[Pullup]
|Voltage   I(typ)   I(min)   I(max)
-1.1V     81.91mA    105.9mA    68.41mA
-1.03V    47.47mA    68.56mA    38.15mA
-962mV    27.53mA    41.2mA     25.58mA
-894mV    19.18mA    24.51mA    21.13mA
-792mV    14.31mA    14.06mA    16.92mA
-316mV    3.287mA    2.986mA    3.66mA
1.622V    -13.09mA   -14.09mA   -12.9mA
1.894V    -28.68mA   -29.62mA   -29.76mA
2.03V     -40.08mA   -44.96mA   -42.32mA
2.098V    -48.2mA    -61.22mA   -49.01mA
2.166V    -63.47mA   -87.06mA   -57.31mA
2.2V      -75.63mA   -103.3mA   -63.79mA
[Ramp]
| variable   typ   min   max
dV/dt_r   0.204/0.181n   0.186/0.221n   0.222/0.161n
dV/dt_f   0.290/0.126n   0.266/0.162n   0.322/0.104n
R_load = 50.000
[Rising Waveform]
R_fixture= 50.000
V_fixture= 0.0
V_fixture_min= 0.0
V_fixture_max= 0.0
|time   V(typ)   V(min)   V(max)
0s        1.483uV    8.334uV    614.8nV
375ps     63.73uV    71.27uV    654.1uV
484ps     3.127mV    -450.1uV   148.3mV
553ps     65.12mV    -2.231mV   249.3mV
635ps     181.6mV    23.18mV    315.8mV
745ps     277.3mV    133.3mV    352.4mV
896ps     324.2mV    246.4mV    366.4mV
1.086ns   337.5mV    295.1mV    369.5mV
1.446ns   340.1mV    309.6mV    369.9mV
10ns      340.1mV    310.4mV    369.8mV
[Rising Waveform]
R_fixture= 50.000
V_fixture= 0.550
V_fixture_min= 0.534
V_fixture_max= 0.568
|time   V(typ)   V(min)   V(max)
0s        308.2mV    312.4mV    298.4mV
392ps     308.1mV    312.5mV    303mV
427ps     307.7mV    312.5mV    349.3mV
499ps     315.2mV    311.9mV    558.1mV
611ps     537.2mV    324.2mV    712.8mV
663ps     616mV      395.5mV    740mV
835ps     714.6mV    617.9mV    767.9mV
1.014ns   731.6mV    681.7mV    771.5mV
1.346ns   734.6mV    698.4mV    771.9mV
10ns      734.6mV    699.4mV    771.8mV
[Falling Waveform]
R_fixture= 50.000
V_fixture= 0.550
V_fixture_min= 0.534
V_fixture_max= 0.568
|time   V(typ)   V(min)   V(max)
0s        734.6mV    699.4mV    771.8mV
385ps     735.9mV    699.5mV    767.8mV
414ps     737.1mV    699.9mV    711.5mV
479ps     730.2mV    701.6mV    475.2mV
540ps     609.8mV    701.1mV    370.3mV
625ps     413.4mV    639.2mV    321.1mV
763ps     328.6mV    403mV      302.8mV
933ps     312mV      330.2mV    299.1mV
1.323ns   308.3mV    313.6mV    298.4mV
10ns      308.2mV    312.4mV    298.4mV
[Falling Waveform]
R_fixture= 50.000
V_fixture= 0.0
V_fixture_min= 0.0
V_fixture_max= 0.0
|time   V(typ)   V(min)   V(max)
0s        340.1mV    310.4mV    369.8mV
374ps     341.8mV    310.5mV    368.6mV
463ps     339.9mV    313.4mV    127mV
550ps     158.8mV    310.2mV    33.66mV
596ps     82.64mV    265.6mV    17.77mV
676ps     28.31mV    117.6mV    6.382mV
733ps     14.13mV    57.38mV    3.23mV
873ps     3.121mV    11.87mV    620.8uV
1.223ns   36.72uV    689.4uV    -68.71uV
10ns      1.486uV    8.334uV    620.4nV
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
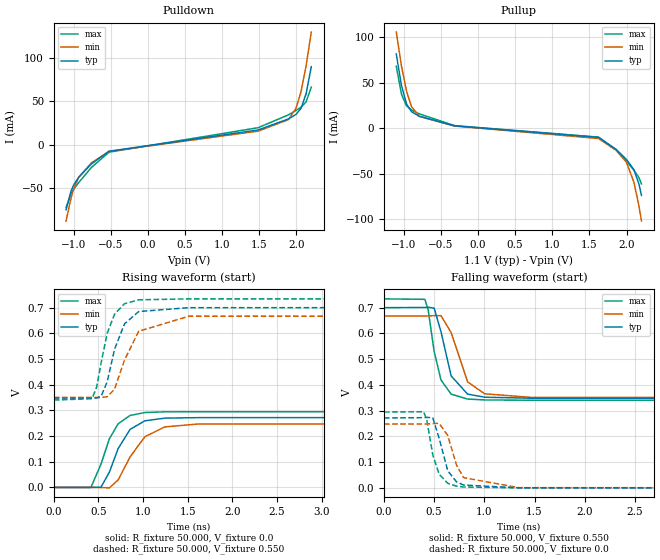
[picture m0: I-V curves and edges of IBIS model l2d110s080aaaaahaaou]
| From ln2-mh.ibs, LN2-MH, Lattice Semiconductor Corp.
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|   Model l2d110s080aaaaahaaou
[Model] l2d110s080aaaaahaaou
Model_type Output
Polarity   Non-Inverting
Enable   Active-High
Vmeas =  0.550V
Cref =  20.000pF
Rref =  50.000
Vref =  0.600V
C_comp   2.000pF   1.500pF   2.500pF
[Temperature Range]   25.000   0.125k   -40.000
[Voltage Range]   1.100V   1.070V   1.130V
[C Comp Corner]
C_comp   2.000pF   1.500pF   2.500pF
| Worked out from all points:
|   slope of the pulldown table from 0 to 0.165 V, typ, clamps not added: 86.1 ohm
|   slope of the pullup table from 0 to 0.165 V, typ, clamps not added: 128 ohm
|   rising waveform, R_fixture 50.000, V_fixture 0.0: 20-80 % time 214ps typ, 268ps min, 193ps max; typ from 0 V to 0.272 V
|   rising waveform, R_fixture 50.000, V_fixture 0.550: 20-80 % time 176ps typ, 222ps min, 154ps max; typ from 0.348 V to 0.7 V
|   falling waveform, R_fixture 50.000, V_fixture 0.550: 20-80 % time 131ps typ, 162ps min, 113ps max; typ from 0.7 V to 0.348 V
|   falling waveform, R_fixture 50.000, V_fixture 0.0: 20-80 % time 115ps typ, 134ps min, 102ps max; typ from 0.272 V to 0 V
[Pulldown]
|Voltage   I(typ)   I(min)   I(max)
-1.1V     -74.9mA    -87.89mA   -72.18mA
-1.032V   -53.02mA   -60.87mA   -56.17mA
-998mV    -46.3mA    -50.95mA   -51.37mA
-930mV    -37.42mA   -37.49mA   -43.53mA
-760mV    -22.08mA   -20.87mA   -26.16mA
-522mV    -7.412mA   -7.551mA   -8.455mA
1.484V    17.14mA    15.77mA    19.72mA
1.892V    29.86mA    29.06mA    34.55mA
1.994V    35.1mA     42.09mA    39.64mA
2.062V    42.16mA    61.38mA    43.43mA
2.13V     58.86mA    91.09mA    49.58mA
2.2V      90.15mA    130.1mA    66.6mA
[Pullup]
|Voltage   I(typ)   I(min)   I(max)
-1.1V     81.52mA    105.6mA    67.94mA
-1.03V    46.8mA     68.07mA    37.3mA
-962mV    26.53mA    40.47mA    24.41mA
-894mV    18mA       23.55mA    19.89mA
-792mV    13.08mA    12.94mA    15.68mA
-316mV    2.479mA    2.28mA     2.753mA
1.622V    -10.23mA   -11.44mA   -9.894mA
1.86V     -23.41mA   -24.54mA   -24.05mA
1.996V    -34.28mA   -37.3mA    -36.36mA
2.098V    -45.67mA   -59.37mA   -46.19mA
2.166V    -61.46mA   -85.7mA    -54.64mA
2.2V      -73.96mA   -102.1mA   -61.39mA
[Ramp]
| variable   typ   min   max
dV/dt_r   0.163/0.215n   0.149/0.268n   0.177/0.193n
dV/dt_f   0.242/0.145n   0.220/0.184n   0.271/0.123n
R_load = 50.000
[Rising Waveform]
R_fixture= 50.000
V_fixture= 0.0
V_fixture_min= 0.0
V_fixture_max= 0.0
|time   V(typ)   V(min)   V(max)
0s        1.706uV    9.484uV    714.8nV
415ps     -43.94uV   180.6uV    -319.1uV
528ps     863.7uV    -654.1uV   90.62mV
622ps     59.47mV    -1.758mV   189.4mV
720ps     151.2mV    28.85mV    247.8mV
854ps     226.1mV    119mV      280.4mV
1.02ns    259.5mV    197.7mV    291.7mV
1.244ns   269.9mV    235.8mV    294.4mV
1.62ns    271.7mV    247mV      294.7mV
10ns      271.6mV    247.9mV    294.6mV
[Rising Waveform]
R_fixture= 50.000
V_fixture= 0.550
V_fixture_min= 0.534
V_fixture_max= 0.568
|time   V(typ)   V(min)   V(max)
0s        348.1mV    350.2mV    340.4mV
428ps     348mV      350.4mV    345.5mV
479ps     348.2mV    350.2mV    390.1mV
532ps     356.7mV    350mV      489.8mV
598ps     411.9mV    353.5mV    600.9mV
680ps     538.3mV    382.1mV    675.1mV
791ps     637.1mV    495.9mV    715.4mV
950ps     685.1mV    608.2mV    730.8mV
1.51ns    700.2mV    666.8mV    734.5mV
10ns      700.2mV    667.8mV    734.4mV
[Falling Waveform]
R_fixture= 50.000
V_fixture= 0.550
V_fixture_min= 0.534
V_fixture_max= 0.568
|time   V(typ)   V(min)   V(max)
0s        700.2mV    667.8mV    734.4mV
407ps     700.9mV    667.9mV    732.6mV
440ps     701.9mV    668.1mV    691.7mV
500ps     698.2mV    669.2mV    529.2mV
568ps     606.3mV    669.3mV    419mV
669ps     434.9mV    603mV      364mV
833ps     364.3mV    411.8mV    345.1mV
1.003ns   352.2mV    365.5mV    341.6mV
1.468ns   348.3mV    351.5mV    340.4mV
10ns      348.1mV    350.2mV    340.4mV
[Falling Waveform]
R_fixture= 50.000
V_fixture= 0.0
V_fixture_min= 0.0
V_fixture_max= 0.0
|time   V(typ)   V(min)   V(max)
0s        271.6mV    247.9mV    294.6mV
395ps     272.7mV    248mV      295.9mV
426ps     273.8mV    248.3mV    263.8mV
486ps     272.5mV    249.8mV    128.2mV
549ps     193.1mV    250.7mV    53.03mV
635ps     66.24mV    203.8mV    17.63mV
723ps     23.14mV    87.97mV    6.499mV
793ps     10.87mV    39.55mV    3.219mV
1.344ns   113.6uV    651.7uV    -22.65uV
10ns      1.705uV    9.477uV    718.9nV
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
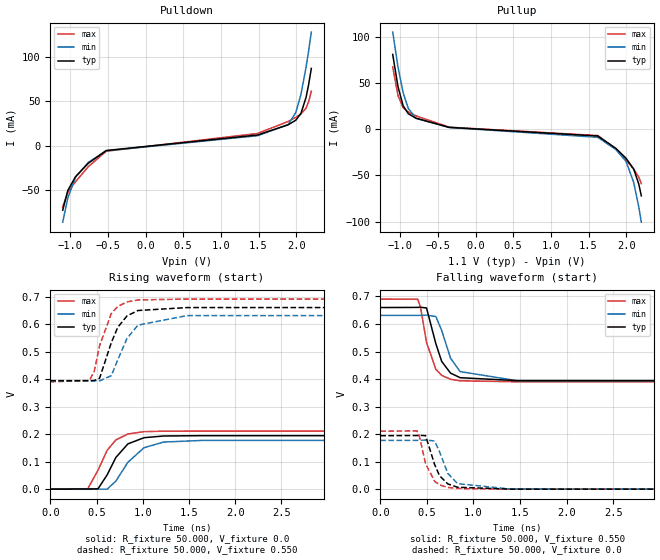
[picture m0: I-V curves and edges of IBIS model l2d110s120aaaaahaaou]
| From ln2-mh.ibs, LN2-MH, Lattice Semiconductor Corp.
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|   Model l2d110s120aaaaahaaou
[Model] l2d110s120aaaaahaaou
Model_type Output
Polarity   Non-Inverting
Enable   Active-High
Vmeas =  0.550V
Cref =  20.000pF
Rref =  50.000
Vref =  0.600V
C_comp   2.000pF   1.500pF   2.500pF
[Temperature Range]   25.000   0.125k   -40.000
[Voltage Range]   1.100V   1.070V   1.130V
[C Comp Corner]
C_comp   2.000pF   1.500pF   2.500pF
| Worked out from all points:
|   slope of the pulldown table from 0 to 0.165 V, typ, clamps not added: 126 ohm
|   slope of the pullup table from 0 to 0.165 V, typ, clamps not added: 191 ohm
|   rising waveform, R_fixture 50.000, V_fixture 0.0: 20-80 % time 209ps typ, 249ps min, 192ps max; typ from 0 V to 0.194 V
|   rising waveform, R_fixture 50.000, V_fixture 0.550: 20-80 % time 173ps typ, 207ps min, 155ps max; typ from 0.394 V to 0.66 V
|   falling waveform, R_fixture 50.000, V_fixture 0.550: 20-80 % time 139ps typ, 164ps min, 123ps max; typ from 0.66 V to 0.394 V
|   falling waveform, R_fixture 50.000, V_fixture 0.0: 20-80 % time 126ps typ, 141ps min, 115ps max; typ from 0.194 V to 0 V
[Pulldown]
|Voltage   I(typ)   I(min)   I(max)
-1.1V     -72.72mA   -86.23mA   -69.18mA
-1.032V   -50.49mA   -58.98mA   -52.58mA
-930mV    -35.09mA   -35.5mA    -40.7mA
-760mV    -19.94mA   -18.95mA   -23.73mA
-522mV    -5.596mA   -5.943mA   -6.368mA
1.484V    11.8mA     10.98mA    13.51mA
1.892V    23.36mA    23.46mA    27.01mA
1.994V    28.49mA    37.15mA    31.75mA
2.062V    36.06mA    57.37mA    35.42mA
2.13V     54.1mA     87.94mA    42.07mA
2.164V    68.38mA    106.4mA    49.14mA
2.2V      86.75mA    127.6mA    61.15mA
[Pullup]
|Voltage   I(typ)   I(min)   I(max)
-1.1V     80.97mA    105.1mA    67.38mA
-1.03V    46.03mA    67.42mA    36.42mA
-962mV    25.5mA     39.64mA    23.27mA
-894mV    16.82mA    22.55mA    18.69mA
-792mV    11.87mA    11.82mA    14.46mA
-350mV    1.926mA    1.847mA    2.152mA
1.622V    -7.397mA   -8.8mA     -6.95mA
1.86V     -20.65mA   -21.86mA   -21.27mA
1.996V    -31.38mA   -34.74mA   -33.39mA
2.098V    -43mA      -57.38mA   -43.23mA
2.166V    -59.35mA   -84.12mA   -51.95mA
2.2V      -72.16mA   -100.7mA   -59.01mA
[Ramp]
| variable   typ   min   max
dV/dt_r   0.117/0.209n   0.106/0.250n   0.126/0.193n
dV/dt_f   0.187/0.153n   0.168/0.187n   0.212/0.134n
R_load = 50.000
[Rising Waveform]
R_fixture= 50.000
V_fixture= 0.0
V_fixture_min= 0.0
V_fixture_max= 0.0
|time   V(typ)   V(min)   V(max)
0s        1.968uV    10.82uV    835.4nV
403ps     160.6uV    157uV      -284.6uV
516ps     938.2uV    -220.8uV   68.43mV
615ps     51.54mV    -268.7uV   140.9mV
709ps     114.8mV    28.86mV    178.6mV
840ps     164.4mV    97.61mV    200.5mV
1.014ns   186.8mV    150.4mV    208.7mV
1.225ns   193mV      170.9mV    210.5mV
1.64ns    194.2mV    176.9mV    210.8mV
10ns      194.2mV    177.2mV    210.7mV
[Rising Waveform]
R_fixture= 50.000
V_fixture= 0.550
V_fixture_min= 0.534
V_fixture_max= 0.568
|time   V(typ)   V(min)   V(max)
0s        394.1mV    393.4mV    390mV
423ps     394.1mV    393.6mV    394.5mV
476ps     394.6mV    393.4mV    428.8mV
533ps     402.7mV    393.3mV    521mV
660ps     532.2mV    412.2mV    638.1mV
730ps     588.2mV    469.8mV    663.8mV
830ps     629.5mV    548.2mV    680.4mV
949ps     649.1mV    596mV      687.5mV
1.479ns   659.8mV    630.6mV    690.7mV
10ns      659.8mV    631.2mV    690.6mV
[Falling Waveform]
R_fixture= 50.000
V_fixture= 0.550
V_fixture_min= 0.534
V_fixture_max= 0.568
|time   V(typ)   V(min)   V(max)
0s        659.8mV    631.2mV    690.6mV
402ps     660.3mV    631.2mV    689.8mV
432ps     660.9mV    631.3mV    661.4mV
496ps     658.3mV    632.2mV    533.3mV
596ps     528.5mV    627.1mV    435.9mV
659ps     464.1mV    576.2mV    413.3mV
754ps     421.5mV    475.8mV    399.1mV
857ps     404.9mV    427mV      393.7mV
1.467ns   394.3mV    394.2mV    390.1mV
10ns      394.1mV    393.4mV    390mV
[Falling Waveform]
R_fixture= 50.000
V_fixture= 0.0
V_fixture_min= 0.0
V_fixture_max= 0.0
|time   V(typ)   V(min)   V(max)
0s        194.2mV    177.2mV    210.7mV
393ps     194.9mV    177.2mV    211.7mV
419ps     195.6mV    177.4mV    192.9mV
486ps     194.5mV    178.6mV    92.44mV
583ps     89.44mV    175.1mV    28.71mV
636ps     48.87mV    135.8mV    15.85mV
724ps     19.16mV    57.46mV    6.356mV
829ps     6.968mV    20.08mV    2.436mV
1.394ns   162.9uV    499.5uV    35uV
10ns      1.966uV    10.81uV    838.6nV
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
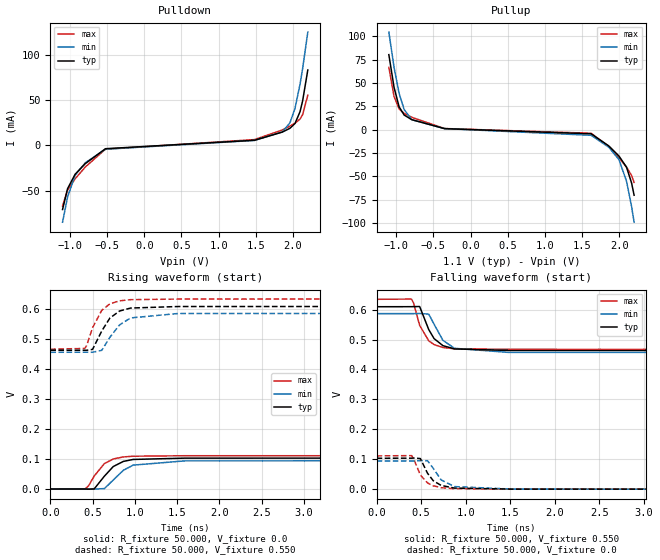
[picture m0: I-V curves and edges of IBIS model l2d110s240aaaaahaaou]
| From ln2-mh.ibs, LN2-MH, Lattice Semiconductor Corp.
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|   Model l2d110s240aaaaahaaou
[Model] l2d110s240aaaaahaaou
Model_type Output
Polarity   Non-Inverting
Enable   Active-High
Vmeas =  0.550V
Cref =  20.000pF
Rref =  50.000
Vref =  0.600V
C_comp   2.000pF   1.500pF   2.500pF
[Temperature Range]   25.000   0.125k   -40.000
[Voltage Range]   1.100V   1.070V   1.130V
[C Comp Corner]
C_comp   2.000pF   1.500pF   2.500pF
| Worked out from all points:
|   slope of the pulldown table from 0 to 0.165 V, typ, clamps not added: 267 ohm
|   slope of the pullup table from 0 to 0.165 V, typ, clamps not added: 387 ohm
|   rising waveform, R_fixture 50.000, V_fixture 0.0: 20-80 % time 197ps typ, 232ps min, 181ps max; typ from 0 V to 0.103 V
|   rising waveform, R_fixture 50.000, V_fixture 0.550: 20-80 % time 185ps typ, 222ps min, 167ps max; typ from 0.463 V to 0.61 V
|   falling waveform, R_fixture 50.000, V_fixture 0.550: 20-80 % time 148ps typ, 165ps min, 136ps max; typ from 0.61 V to 0.463 V
|   falling waveform, R_fixture 50.000, V_fixture 0.0: 20-80 % time 142ps typ, 154ps min, 133ps max; typ from 0.103 V to 0 V
[Pulldown]
|Voltage   I(typ)   I(min)   I(max)
-1.1V     -70.48mA   -84.41mA   -66.47mA
-1.032V   -47.45mA   -56.65mA   -49mA
-930mV    -31.54mA   -32.58mA   -36.61mA
-794mV    -19.97mA   -19.02mA   -23.71mA
-522mV    -3.537mA   -4.129mA   -4.009mA
1.484V    5.747mA    5.596mA    6.505mA
1.858V    14.78mA    15mA       17.13mA
1.96V     18.95mA    25mA       21.38mA
2.028V    24.23mA    40.98mA    24.5mA
2.096V    37.34mA    67.59mA    29.2mA
2.13V     48.92mA    84.48mA    33.88mA
2.2V      83.05mA    124.8mA    55.4mA
[Pullup]
|Voltage   I(typ)   I(min)   I(max)
-1.1V     80.41mA    104.6mA    66.79mA
-1.03V    45.25mA    66.76mA    35.51mA
-962mV    24.45mA    38.8mA     22.09mA
-894mV    15.63mA    21.53mA    17.44mA
-792mV    10.64mA    10.68mA    13.21mA
-350mV    1.031mA    1.067mA    1.152mA
1.622V    -4.519mA   -6.12mA    -3.927mA
1.86V     -17.57mA   -18.98mA   -18.12mA
1.996V    -28.35mA   -32.13mA   -30.22mA
2.098V    -40.35mA   -55.36mA   -40.27mA
2.166V    -57.26mA   -82.54mA   -49.29mA
2.2V      -70.38mA   -99.32mA   -56.65mA
[Ramp]
| variable   typ   min   max
dV/dt_r   61.967m/0.198n   56.611m/0.233n   66.721m/0.181n
dV/dt_f   0.104/0.158n   92.372m/0.182n   0.120/0.143n
R_load = 50.000
[Rising Waveform]
R_fixture= 50.000
V_fixture= 0.0
V_fixture_min= 0.0
V_fixture_max= 0.0
|time   V(typ)   V(min)   V(max)
0s        2.356uV    12.75uV    1.02uV
409ps     146uV      190.9uV    -284.1uV
453ps     -470.3uV   279.5uV    10.67mV
519ps     314.5uV    -190.9uV   43.24mV
640ps     42.94mV    1.477mV    85.15mV
745ps     75.21mV    30.15mV    100.4mV
865ps     92.31mV    62.79mV    107.2mV
980ps     98.8mV     79.83mV    109.6mV
1.595ns   103.2mV    94.08mV    111.2mV
10ns      103.3mV    94.36mV    111.2mV
[Rising Waveform]
R_fixture= 50.000
V_fixture= 0.550
V_fixture_min= 0.534
V_fixture_max= 0.568
|time   V(typ)   V(min)   V(max)
0s        463.4mV    456.7mV    467.1mV
407ps     463.5mV    456.9mV    469.5mV
430ps     463.4mV    456.9mV    478.9mV
500ps     466.4mV    456.7mV    538.8mV
609ps     528.1mV    463.3mV    597mV
705ps     571.1mV    506.9mV    618.6mV
819ps     594.6mV    548.1mV    628.6mV
950ps     604.5mV    571.5mV    632.5mV
1.51ns    609.6mV    586.3mV    634.5mV
10ns      609.7mV    586.7mV    634.5mV
[Falling Waveform]
R_fixture= 50.000
V_fixture= 0.550
V_fixture_min= 0.534
V_fixture_max= 0.568
|time   V(typ)   V(min)   V(max)
0s        609.7mV    586.6mV    634.5mV
391ps     609.8mV    586.6mV    635.3mV
415ps     610.1mV    586.6mV    622.1mV
483ps     610.3mV    587.1mV    547.3mV
585ps     533.3mV    585mV      495.7mV
645ps     503.1mV    551.1mV    483.1mV
744ps     479.6mV    497.4mV    473.4mV
874ps     468.7mV    470.7mV    469.2mV
1.476ns   463.6mV    457.1mV    467.3mV
10ns      463.4mV    456.7mV    467.1mV
[Falling Waveform]
R_fixture= 50.000
V_fixture= 0.0
V_fixture_min= 0.0
V_fixture_max= 0.0
|time   V(typ)   V(min)   V(max)
0s        103.3mV    94.36mV    111.2mV
393ps     103.6mV    94.35mV    112.1mV
415ps     104mV      94.4mV     102mV
491ps     102.3mV    95.25mV    47.16mV
571ps     53.34mV    95.13mV    20.88mV
636ps     28.11mV    69.62mV    11.13mV
724ps     12.5mV     30.86mV    4.983mV
873ps     3.584mV    8.568mV    1.516mV
1.513ns   211.2uV    329.8uV    155.8uV
10ns      2.355uV    12.73uV    1.021uV
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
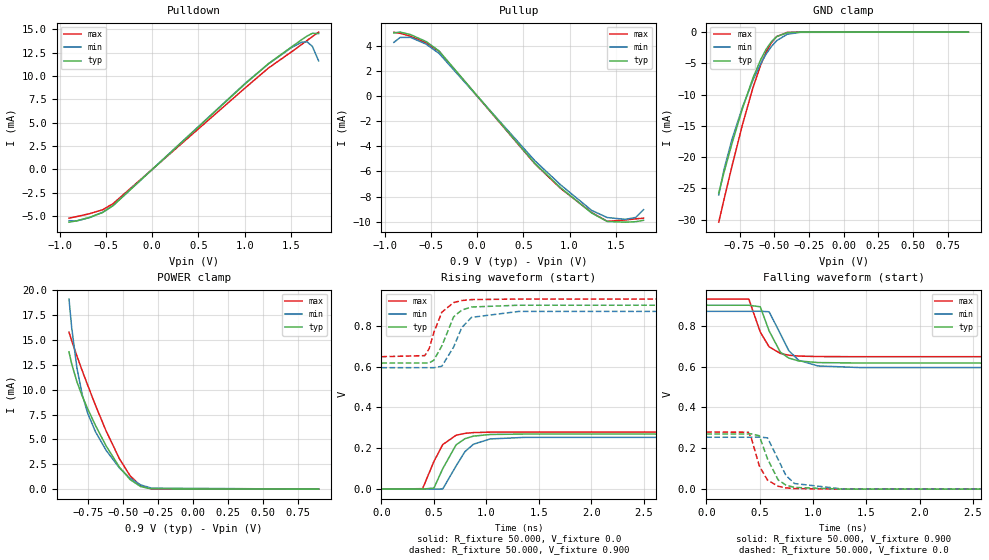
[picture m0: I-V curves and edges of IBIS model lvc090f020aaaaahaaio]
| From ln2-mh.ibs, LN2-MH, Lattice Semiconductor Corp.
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|   Model lvc090f020aaaaahaaio
[Model] lvc090f020aaaaahaaio
| Clamp models do not include dynamic input termination. Please refer to
| the lvc090axxxaaaaahaain model for input termination.
Model_type I/O
Polarity   Non-Inverting
Enable   Active-Low
Vinl =  0.300V
Vinh =  0.600V
Vmeas =  0.500V
Cref =  0.0F
Rref =  1.000M
Vref =  0.0V
C_comp   2.000pF   1.500pF   2.500pF
[Temperature Range]   25.000   0.125k   -40.000
[Voltage Range]   0.900V   0.870V   0.930V
[C Comp Corner]
C_comp   2.000pF   1.500pF   2.500pF
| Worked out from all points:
|   slope of the pulldown table from 0 to 0.135 V, typ, clamps not added: 108 ohm
|   slope of the pullup table from 0 to 0.135 V, typ, clamps not added: 111 ohm
|   GND clamp passes 1 mA (typ) near -0.50 V on its own axis
|   POWER clamp passes 1 mA (typ) near -0.45 V on its own axis
|   rising waveform, R_fixture 50.000, V_fixture 0.0: 20-80 % time 162ps typ, 181ps min, 151ps max; typ from 0 V to 0.27 V
|   rising waveform, R_fixture 50.000, V_fixture 0.900: 20-80 % time 133ps typ, 152ps min, 119ps max; typ from 0.617 V to 0.9 V
|   falling waveform, R_fixture 50.000, V_fixture 0.900: 20-80 % time 142ps typ, 166ps min, 131ps max; typ from 0.9 V to 0.617 V
|   falling waveform, R_fixture 50.000, V_fixture 0.0: 20-80 % time 125ps typ, 140ps min, 117ps max; typ from 0.27 V to 0 V
[Pulldown]
|Voltage   I(typ)   I(min)   I(max)
-900mV    -5.663mA   -5.504mA   -5.226mA
-816mV    -5.515mA   -5.529mA   -5.062mA
-676mV    -5.144mA   -5.168mA   -4.747mA
-536mV    -4.619mA   -4.596mA   -4.33mA
-424mV    -3.885mA   -3.89mA    -3.679mA
1.004V    9.15mA     9.206mA    8.717mA
1.256V    11.32mA    11.29mA    10.85mA
1.508V    13.13mA    13.06mA    12.6mA
1.62V     13.92mA    13.64mA    13.41mA
1.676V    14.29mA    13.66mA    13.82mA
1.732V    14.58mA    13.18mA    14.23mA
1.8V      14.55mA    11.62mA    14.71mA
[Pullup]
|Voltage   I(typ)   I(min)   I(max)
-900mV    5mA        4.254mA    5.055mA
-832mV    5.071mA    4.645mA    4.974mA
-720mV    4.872mA    4.653mA    4.739mA
-552mV    4.323mA    4.114mA    4.223mA
-412mV    3.575mA    3.382mA    3.541mA
624mV     -5.348mA   -5.138mA   -5.388mA
904mV     -7.299mA   -7.068mA   -7.349mA
1.24V     -9.304mA   -9.097mA   -9.27mA
1.408V    -9.974mA   -9.662mA   -9.959mA
1.604V    -10.03mA   -9.805mA   -9.853mA
1.716V    -9.99mA    -9.654mA   -9.766mA
1.8V      -9.881mA   -9.037mA   -9.711mA
[GND_clamp]
|Voltage   I(typ)   I(min)   I(max)
-900mV    -25.74mA   -26.04mA   -30.41mA
-862mV    -22.43mA   -21.97mA   -26.77mA
-805mV    -17.85mA   -17.2mA    -21.48mA
-729mV    -12.23mA   -12.01mA   -14.81mA
-653mV    -7.318mA   -7.665mA   -8.863mA
-596mV    -4.322mA   -4.979mA   -5.166mA
-558mV    -2.736mA   -3.498mA   -3.192mA
-520mV    -1.528mA   -2.289mA   -1.69mA
-482mV    -716.8uA   -1.366mA   -707.5uA
-406mV    -84.93uA   -343.7uA   -48.42uA
-311mV    -3.638uA   -36.43uA   -951.8nA
900mV     -18.59pA   0A         -11.79pA
[POWER_clamp]
|Voltage   I(typ)   I(min)   I(max)
-886mV    13.81mA    19.12mA    15.79mA
-867mV    12.61mA    16.27mA    14.94mA
-829mV    10.78mA    12.15mA    13.38mA
-791mV    9.351mA    9.485mA    11.9mA
-753mV    8.099mA    7.665mA    10.48mA
-696mV    6.388mA    5.752mA    8.409mA
-620mV    4.338mA    3.895mA    5.839mA
-525mV    2.205mA    2.133mA    3.051mA
-449mV    967uA      1.099mA    1.349mA
-373mV    256.9uA    426.8uA    331.7uA
-297mV    30.15uA    106.2uA    25.19uA
900mV     0A         0A         0A
[Ramp]
| variable   typ   min   max
dV/dt_r   0.162/0.162n   0.152/0.182n   0.168/0.151n
dV/dt_f   0.170/0.143n   0.166/0.167n   0.169/0.131n
R_load = 50.000
[Rising Waveform]
R_fixture= 50.000
V_fixture= 0.0
V_fixture_min= 0.0
V_fixture_max= 0.0
|time   V(typ)   V(min)   V(max)
0s        1.599uV    8.537uV    733nV
392ps     232.9uV    125.4uV    2.295mV
500ps     5.337mV    -101.8uV   135.7mV
584ps     100.2mV    954.2uV    218.2mV
711ps     216.7mV    113.5mV    263.6mV
795ps     246.7mV    183.4mV    272.9mV
876ps     259.4mV    219.6mV    276.7mV
1.035ns   267.5mV    245.6mV    278.9mV
1.366ns   269.6mV    253.4mV    279.5mV
10ns      269.8mV    254mV      279.5mV
[Rising Waveform]
R_fixture= 50.000
V_fixture= 0.900
V_fixture_min= 0.870
V_fixture_max= 0.930
|time   V(typ)   V(min)   V(max)
0s        616.9mV    594.2mV    648mV
413ps     617mV      594.3mV    653.3mV
455ps     617.9mV    594.3mV    687.7mV
498ps     630.2mV    594.2mV    764.7mV
575ps     700.4mV    601.1mV    865.6mV
688ps     843.4mV    695.7mV    912.9mV
765ps     876.1mV    790.5mV    922.8mV
858ps     891.2mV    840.5mV    927.4mV
1.307ns   899.9mV    869.5mV    930mV
10ns      900mV      870mV      930mV
[Falling Waveform]
R_fixture= 50.000
V_fixture= 0.900
V_fixture_min= 0.870
V_fixture_max= 0.930
|time   V(typ)   V(min)   V(max)
0s        900mV      870mV      930mV
399ps     899.9mV    870mV      930mV
506ps     892.3mV    870.4mV    768.8mV
589ps     774.5mV    867.9mV    696.6mV
694ps     670.5mV    760.7mV    664.2mV
774ps     641.2mV    677.3mV    655.3mV
866ps     627.3mV    630.5mV    651.1mV
1.047ns   619.3mV    602.8mV    648.7mV
1.433ns   617.1mV    595mV      648.1mV
10ns      616.9mV    594.2mV    648mV
[Falling Waveform]
R_fixture= 50.000
V_fixture= 0.0
V_fixture_min= 0.0
V_fixture_max= 0.0
|time   V(typ)   V(min)   V(max)
0s        269.8mV    254mV      279.5mV
394ps     270.1mV    254mV      278.4mV
423ps     270.6mV    254.1mV    248.7mV
497ps     261.3mV    255mV      113.6mV
574ps     148.3mV    251mV      44.22mV
674ps     45.25mV    145.4mV    14.1mV
746ps     20.13mV    67.75mV    6.464mV
827ps     8.542mV    27.57mV    2.789mV
1.287ns   186uV      544.6uV    73.56uV
10ns      1.59uV     8.533uV    727.4nV
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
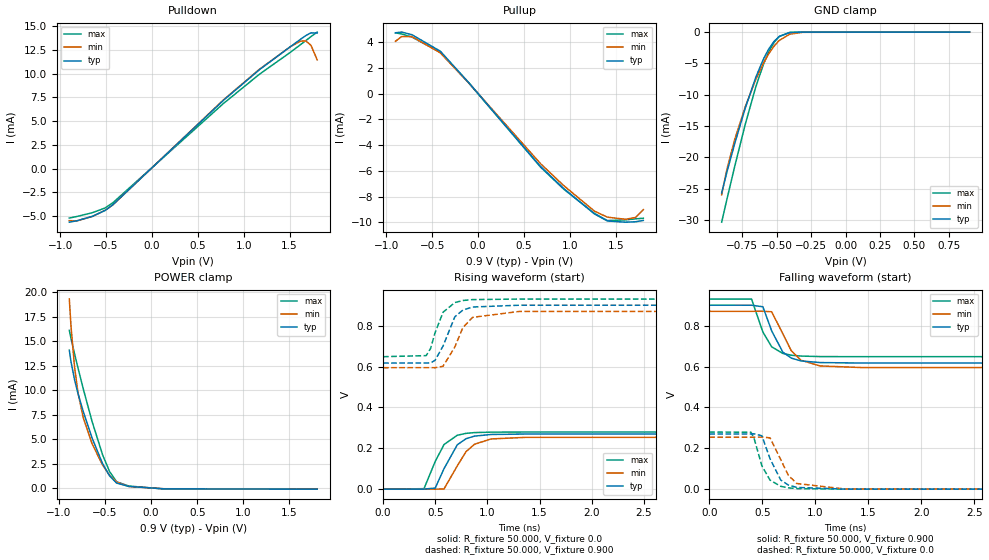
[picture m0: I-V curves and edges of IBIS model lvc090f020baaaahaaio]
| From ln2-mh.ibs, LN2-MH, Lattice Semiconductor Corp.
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|   Model lvc090f020baaaahaaio
[Model] lvc090f020baaaahaaio
| Clamp models do not include dynamic input termination. Please refer to
| the lvc090axxxbaaaahaain model for input termination.
Model_type I/O
Polarity   Non-Inverting
Enable   Active-Low
Vinl =  0.300V
Vinh =  0.600V
Vmeas =  0.500V
Cref =  0.0F
Rref =  1.000M
Vref =  0.0V
C_comp   2.000pF   1.500pF   2.500pF
[Temperature Range]   25.000   0.125k   -40.000
[Voltage Range]   0.900V   0.870V   0.930V
[C Comp Corner]
C_comp   2.000pF   1.500pF   2.500pF
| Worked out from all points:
|   slope of the pulldown table from 0 to 0.135 V, typ, clamps not added: 108 ohm
|   slope of the pullup table from 0 to 0.135 V, typ, clamps not added: 117 ohm
|   GND clamp passes 1 mA (typ) near -0.50 V on its own axis
|   POWER clamp passes 1 mA (typ) near -0.43 V on its own axis
|   rising waveform, R_fixture 50.000, V_fixture 0.0: 20-80 % time 162ps typ, 181ps min, 151ps max; typ from 0 V to 0.27 V
|   rising waveform, R_fixture 50.000, V_fixture 0.900: 20-80 % time 133ps typ, 152ps min, 119ps max; typ from 0.617 V to 0.9 V
|   falling waveform, R_fixture 50.000, V_fixture 0.900: 20-80 % time 142ps typ, 166ps min, 131ps max; typ from 0.9 V to 0.617 V
|   falling waveform, R_fixture 50.000, V_fixture 0.0: 20-80 % time 125ps typ, 140ps min, 117ps max; typ from 0.27 V to 0 V
[Pulldown]
|Voltage   I(typ)   I(min)   I(max)
-900mV    -5.638mA   -5.478mA   -5.202mA
-816mV    -5.487mA   -5.499mA   -5.034mA
-648mV    -5.015mA   -5.03mA    -4.637mA
-508mV    -4.396mA   -4.378mA   -4.132mA
-424mV    -3.787mA   -3.801mA   -3.579mA
780mV     7.203mA    7.25mA     6.868mA
1.172V    10.43mA    10.47mA    9.948mA
1.508V    12.84mA    12.84mA    12.25mA
1.62V     13.63mA    13.43mA    13.07mA
1.676V    14.01mA    13.45mA    13.48mA
1.732V    14.3mA     12.99mA    13.9mA
1.8V      14.28mA    11.46mA    14.38mA
[Pullup]
|Voltage   I(typ)   I(min)   I(max)
-900mV    4.734mA    4.076mA    4.733mA
-832mV    4.79mA     4.442mA    4.643mA
-720mV    4.584mA    4.436mA    4.4mA
-412mV    3.306mA    3.179mA    3.213mA
-104mV    874.4uA    851.4uA    856.1uA
680mV     -5.664mA   -5.444mA   -5.709mA
932mV     -7.374mA   -7.146mA   -7.42mA
1.268V    -9.357mA   -9.139mA   -9.314mA
1.408V    -9.898mA   -9.602mA   -9.871mA
1.604V    -9.995mA   -9.77mA    -9.815mA
1.716V    -9.961mA   -9.626mA   -9.737mA
1.8V      -9.856mA   -9.013mA   -9.686mA
[GND_clamp]
|Voltage   I(typ)   I(min)   I(max)
-900mV    -25.66mA   -25.96mA   -30.33mA
-862mV    -22.35mA   -21.9mA    -26.69mA
-805mV    -17.77mA   -17.12mA   -21.41mA
-729mV    -12.16mA   -11.94mA   -14.74mA
-653mV    -7.257mA   -7.604mA   -8.799mA
-596mV    -4.271mA   -4.926mA   -5.112mA
-558mV    -2.694mA   -3.452mA   -3.147mA
-520mV    -1.497mA   -2.251mA   -1.658mA
-482mV    -698.8uA   -1.337mA   -690.4uA
-406mV    -81.99uA   -333.1uA   -46.84uA
-311mV    -3.383uA   -34.47uA   -862nA
900mV     0A         0A         0A
[POWER_clamp]
|Voltage   I(typ)   I(min)   I(max)
-886mV    14.08mA    19.3mA     16.11mA
-867mV    12.88mA    16.46mA    15.27mA
-829mV    11.06mA    12.36mA    13.71mA
-791mV    9.635mA    9.695mA    12.24mA
-734mV    7.799mA    7.164mA    10.11mA
-639mV    5.115mA    4.532mA    6.802mA
-525mV    2.491mA    2.349mA    3.394mA
-449mV    1.244mA    1.308mA    1.684mA
-373mV    512.9uA    621.3uA    645.6uA
-240mV    175.8uA    166.1uA    212uA
140mV     -71.31uA   -61.44uA   -81.07uA
1.8V      -102.7uA   -103uA     -104uA
[Ramp]
| variable   typ   min   max
dV/dt_r   0.162/0.162n   0.152/0.182n   0.168/0.151n
dV/dt_f   0.170/0.143n   0.166/0.167n   0.169/0.131n
R_load = 50.000
[Rising Waveform]
R_fixture= 50.000
V_fixture= 0.0
V_fixture_min= 0.0
V_fixture_max= 0.0
|time   V(typ)   V(min)   V(max)
0s        1.599uV    8.537uV    733nV
392ps     232.9uV    125.4uV    2.295mV
500ps     5.337mV    -101.8uV   135.7mV
584ps     100.2mV    954.2uV    218.2mV
711ps     216.7mV    113.5mV    263.6mV
795ps     246.7mV    183.4mV    272.9mV
876ps     259.4mV    219.6mV    276.7mV
1.035ns   267.5mV    245.6mV    278.9mV
1.366ns   269.6mV    253.4mV    279.5mV
10ns      269.8mV    254mV      279.5mV
[Rising Waveform]
R_fixture= 50.000
V_fixture= 0.900
V_fixture_min= 0.870
V_fixture_max= 0.930
|time   V(typ)   V(min)   V(max)
0s        616.9mV    594.2mV    648mV
413ps     617mV      594.3mV    653.3mV
455ps     617.9mV    594.3mV    687.7mV
498ps     630.2mV    594.2mV    764.7mV
575ps     700.4mV    601.1mV    865.6mV
688ps     843.4mV    695.7mV    912.9mV
765ps     876.1mV    790.5mV    922.8mV
858ps     891.2mV    840.5mV    927.4mV
1.307ns   899.9mV    869.5mV    930mV
10ns      900mV      870mV      930mV
[Falling Waveform]
R_fixture= 50.000
V_fixture= 0.900
V_fixture_min= 0.870
V_fixture_max= 0.930
|time   V(typ)   V(min)   V(max)
0s        900mV      870mV      930mV
399ps     899.9mV    870mV      930mV
506ps     892.3mV    870.4mV    768.8mV
589ps     774.5mV    867.9mV    696.6mV
694ps     670.5mV    760.7mV    664.2mV
774ps     641.2mV    677.3mV    655.3mV
866ps     627.3mV    630.5mV    651.1mV
1.047ns   619.3mV    602.8mV    648.7mV
1.433ns   617.1mV    595mV      648.1mV
10ns      616.9mV    594.2mV    648mV
[Falling Waveform]
R_fixture= 50.000
V_fixture= 0.0
V_fixture_min= 0.0
V_fixture_max= 0.0
|time   V(typ)   V(min)   V(max)
0s        269.8mV    254mV      279.5mV
394ps     270.1mV    254mV      278.4mV
423ps     270.6mV    254.1mV    248.7mV
497ps     261.3mV    255mV      113.6mV
574ps     148.3mV    251mV      44.22mV
674ps     45.25mV    145.4mV    14.1mV
746ps     20.13mV    67.75mV    6.464mV
827ps     8.542mV    27.57mV    2.789mV
1.287ns   186uV      544.6uV    73.56uV
10ns      1.59uV     8.533uV    727.4nV
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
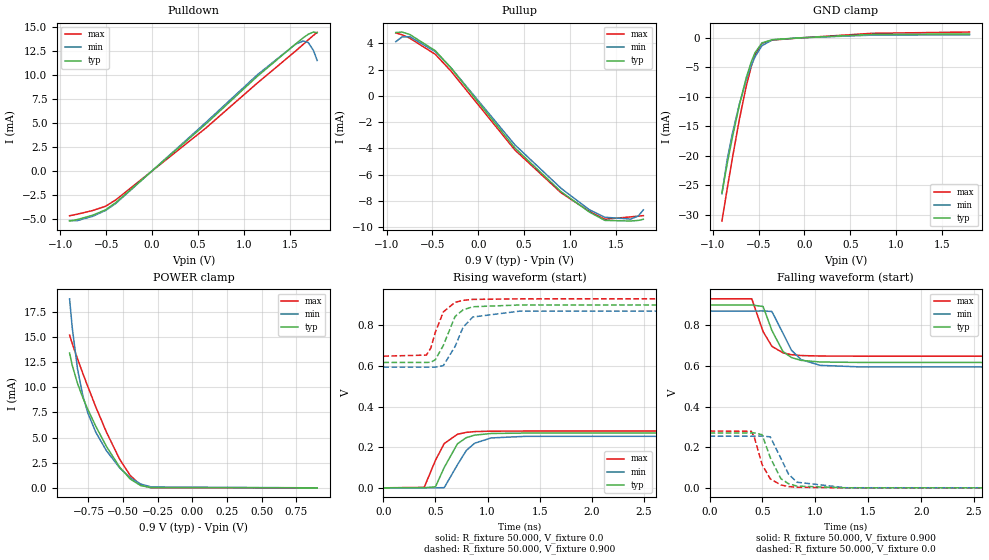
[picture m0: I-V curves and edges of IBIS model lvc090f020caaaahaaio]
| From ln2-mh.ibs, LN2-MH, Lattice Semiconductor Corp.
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|   Model lvc090f020caaaahaaio
[Model] lvc090f020caaaahaaio
| Clamp models do not include dynamic input termination. Please refer to
| the lvc090axxxcaaaahaain model for input termination.
Model_type I/O
Polarity   Non-Inverting
Enable   Active-Low
Vinl =  0.300V
Vinh =  0.600V
Vmeas =  0.500V
Cref =  0.0F
Rref =  1.000M
Vref =  0.0V
C_comp   2.000pF   1.500pF   2.500pF
[Temperature Range]   25.000   0.125k   -40.000
[Voltage Range]   0.900V   0.870V   0.930V
[C Comp Corner]
C_comp   2.000pF   1.500pF   2.500pF
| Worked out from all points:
|   slope of the pulldown table from 0 to 0.135 V, typ, clamps not added: 121 ohm
|   slope of the pullup table from 0 to 0.135 V, typ, clamps not added: 112 ohm
|   GND clamp passes 1 mA (typ) near -0.47 V on its own axis
|   POWER clamp passes 1 mA (typ) near -0.46 V on its own axis
|   rising waveform, R_fixture 50.000, V_fixture 0.0: 20-80 % time 162ps typ, 181ps min, 151ps max; typ from 0 V to 0.27 V
|   rising waveform, R_fixture 50.000, V_fixture 0.900: 20-80 % time 133ps typ, 152ps min, 119ps max; typ from 0.617 V to 0.9 V
|   falling waveform, R_fixture 50.000, V_fixture 0.900: 20-80 % time 142ps typ, 166ps min, 131ps max; typ from 0.9 V to 0.617 V
|   falling waveform, R_fixture 50.000, V_fixture 0.0: 20-80 % time 125ps typ, 140ps min, 117ps max; typ from 0.27 V to 0 V
[Pulldown]
|Voltage   I(typ)   I(min)   I(max)
-900mV    -5.173mA   -5.125mA   -4.627mA
-816mV    -5.022mA   -5.134mA   -4.463mA
-648mV    -4.572mA   -4.681mA   -4.086mA
-508mV    -4.013mA   -4.077mA   -3.645mA
-396mV    -3.26mA    -3.347mA   -2.976mA
584mV     4.889mA    5.046mA    4.469mA
1.144V    9.832mA    9.989mA    9.132mA
1.564V    13.21mA    13.2mA     12.48mA
1.648V    13.86mA    13.53mA    13.18mA
1.704V    14.24mA    13.36mA    13.66mA
1.76V     14.46mA    12.53mA    14.12mA
1.8V      14.38mA    11.51mA    14.43mA
[Pullup]
|Voltage   I(typ)   I(min)   I(max)
-900mV    4.83mA     4.131mA    4.795mA
-832mV    4.869mA    4.495mA    4.662mA
-748mV    4.687mA    4.517mA    4.406mA
-468mV    3.441mA    3.369mA    3.168mA
-300mV    2.152mA    2.165mA    1.911mA
400mV     -3.965mA   -3.728mA   -4.12mA
904mV     -7.295mA   -7.041mA   -7.38mA
1.212V    -8.843mA   -8.668mA   -8.785mA
1.38V     -9.475mA   -9.236mA   -9.382mA
1.66V     -9.522mA   -9.376mA   -9.209mA
1.744V    -9.477mA   -9.144mA   -9.15mA
1.8V      -9.391mA   -8.672mA   -9.112mA
[GND_clamp]
|Voltage   I(typ)   I(min)   I(max)
-900mV    -26.23mA   -26.42mA   -31.01mA
-843mV    -21.35mA   -20.64mA   -25.59mA
-786mV    -16.88mA   -16.2mA    -20.37mA
-710mV    -11.41mA   -11.24mA   -13.83mA
-634mV    -6.729mA   -7.102mA   -8.134mA
-577mV    -3.961mA   -4.589mA   -4.707mA
-539mV    -2.551mA   -3.235mA   -2.953mA
-463mV    -890.5uA   -1.367mA   -946.5uA
-349mV    -352.6uA   -378.2uA   -421.6uA
-45mV     -42.8uA    -36.37uA   -52.77uA
734mV     527.5uA    410.9uA    719.1uA
1.8V      610uA      464.4uA    937.2uA
[POWER_clamp]
|Voltage   I(typ)   I(min)   I(max)
-886mV    13.4mA     18.79mA    15.19mA
-867mV    12.2mA     15.95mA    14.36mA
-829mV    10.39mA    11.85mA    12.84mA
-791mV    8.986mA    9.193mA    11.4mA
-753mV    7.76mA     7.389mA    10.02mA
-696mV    6.096mA    5.502mA    8.018mA
-620mV    4.114mA    3.69mA     5.536mA
-525mV    2.063mA    1.993mA    2.854mA
-449mV    884.5uA    1.009mA    1.231mA
-373mV    221.5uA    379.3uA    279.5uA
-297mV    19.57uA    87.58uA    7.748uA
900mV     0A         0A         0A
[Ramp]
| variable   typ   min   max
dV/dt_r   0.162/0.162n   0.152/0.182n   0.168/0.151n
dV/dt_f   0.170/0.143n   0.166/0.167n   0.169/0.131n
R_load = 50.000
[Rising Waveform]
R_fixture= 50.000
V_fixture= 0.0
V_fixture_min= 0.0
V_fixture_max= 0.0
|time   V(typ)   V(min)   V(max)
0s        1.599uV    8.537uV    733nV
392ps     232.9uV    125.4uV    2.295mV
500ps     5.337mV    -101.8uV   135.7mV
584ps     100.2mV    954.2uV    218.2mV
711ps     216.7mV    113.5mV    263.6mV
795ps     246.7mV    183.4mV    272.9mV
876ps     259.4mV    219.6mV    276.7mV
1.035ns   267.5mV    245.6mV    278.9mV
1.366ns   269.6mV    253.4mV    279.5mV
10ns      269.8mV    254mV      279.5mV
[Rising Waveform]
R_fixture= 50.000
V_fixture= 0.900
V_fixture_min= 0.870
V_fixture_max= 0.930
|time   V(typ)   V(min)   V(max)
0s        616.9mV    594.2mV    648mV
413ps     617mV      594.3mV    653.3mV
455ps     617.9mV    594.3mV    687.7mV
498ps     630.2mV    594.2mV    764.7mV
575ps     700.4mV    601.1mV    865.6mV
688ps     843.4mV    695.7mV    912.9mV
765ps     876.1mV    790.5mV    922.8mV
858ps     891.2mV    840.5mV    927.4mV
1.307ns   899.9mV    869.5mV    930mV
10ns      900mV      870mV      930mV
[Falling Waveform]
R_fixture= 50.000
V_fixture= 0.900
V_fixture_min= 0.870
V_fixture_max= 0.930
|time   V(typ)   V(min)   V(max)
0s        900mV      870mV      930mV
399ps     899.9mV    870mV      930mV
506ps     892.3mV    870.4mV    768.8mV
589ps     774.5mV    867.9mV    696.6mV
694ps     670.5mV    760.7mV    664.2mV
774ps     641.2mV    677.3mV    655.3mV
866ps     627.3mV    630.5mV    651.1mV
1.047ns   619.3mV    602.8mV    648.7mV
1.433ns   617.1mV    595mV      648.1mV
10ns      616.9mV    594.2mV    648mV
[Falling Waveform]
R_fixture= 50.000
V_fixture= 0.0
V_fixture_min= 0.0
V_fixture_max= 0.0
|time   V(typ)   V(min)   V(max)
0s        269.8mV    254mV      279.5mV
394ps     270.1mV    254mV      278.4mV
423ps     270.6mV    254.1mV    248.7mV
497ps     261.3mV    255mV      113.6mV
574ps     148.3mV    251mV      44.22mV
674ps     45.25mV    145.4mV    14.1mV
746ps     20.13mV    67.75mV    6.464mV
827ps     8.542mV    27.57mV    2.789mV
1.287ns   186uV      544.6uV    73.56uV
10ns      1.59uV     8.533uV    727.4nV
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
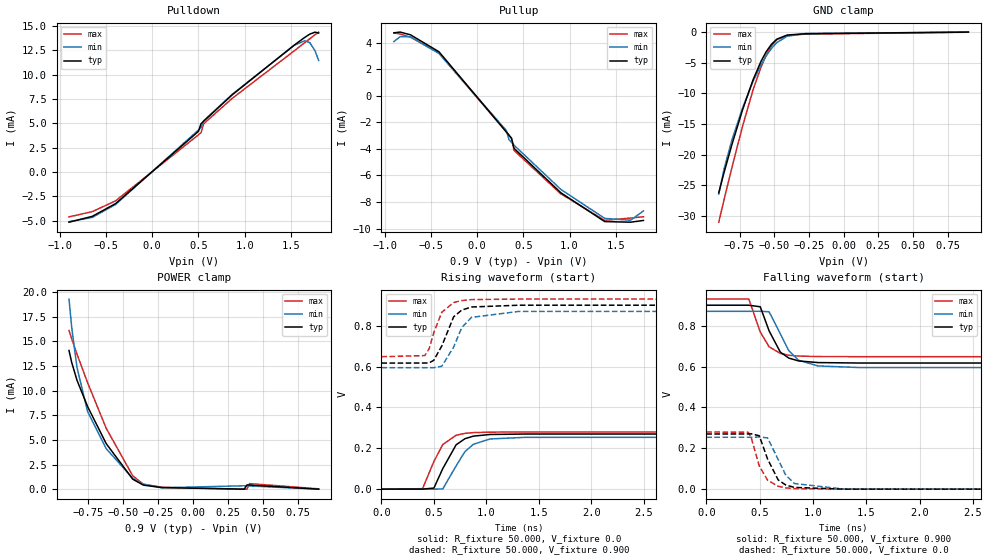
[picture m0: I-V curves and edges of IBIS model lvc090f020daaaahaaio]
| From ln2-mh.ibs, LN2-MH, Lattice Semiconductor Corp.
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|   Model lvc090f020daaaahaaio
[Model] lvc090f020daaaahaaio
| Clamp models do not include dynamic input termination. Please refer to
| the lvc090axxxdaaaahaain model for input termination.
Model_type I/O
Polarity   Non-Inverting
Enable   Active-Low
Vinl =  0.300V
Vinh =  0.600V
Vmeas =  0.500V
Cref =  0.0F
Rref =  1.000M
Vref =  0.0V
C_comp   2.000pF   1.500pF   2.500pF
[Temperature Range]   25.000   0.125k   -40.000
[Voltage Range]   0.900V   0.870V   0.930V
[C Comp Corner]
C_comp   2.000pF   1.500pF   2.500pF
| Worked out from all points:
|   slope of the pulldown table from 0 to 0.135 V, typ, clamps not added: 121 ohm
|   slope of the pullup table from 0 to 0.135 V, typ, clamps not added: 117 ohm
|   GND clamp passes 1 mA (typ) near -0.47 V on its own axis
|   POWER clamp passes 1 mA (typ) near -0.43 V on its own axis
|   rising waveform, R_fixture 50.000, V_fixture 0.0: 20-80 % time 162ps typ, 181ps min, 151ps max; typ from 0 V to 0.27 V
|   rising waveform, R_fixture 50.000, V_fixture 0.900: 20-80 % time 133ps typ, 152ps min, 119ps max; typ from 0.617 V to 0.9 V
|   falling waveform, R_fixture 50.000, V_fixture 0.900: 20-80 % time 142ps typ, 166ps min, 131ps max; typ from 0.9 V to 0.617 V
|   falling waveform, R_fixture 50.000, V_fixture 0.0: 20-80 % time 125ps typ, 140ps min, 117ps max; typ from 0.27 V to 0 V
[Pulldown]
|Voltage   I(typ)   I(min)   I(max)
-900mV    -5.173mA   -5.125mA   -4.627mA
-648mV    -4.572mA   -4.681mA   -4.086mA
-396mV    -3.26mA    -3.347mA   -2.976mA
500mV     4.172mA    4.309mA    3.814mA
528mV     4.952mA    4.554mA    4.031mA
556mV     5.206mA    5.262mA    4.944mA
864mV     7.919mA    7.966mA    7.555mA
1.536V    13.04mA    13.02mA    12.45mA
1.648V    13.82mA    13.48mA    13.28mA
1.704V    14.17mA    13.3mA     13.69mA
1.76V     14.37mA    12.48mA    14.1mA
1.8V      14.28mA    11.46mA    14.38mA
[Pullup]
|Voltage   I(typ)   I(min)   I(max)
-900mV    4.734mA    4.076mA    4.733mA
-832mV    4.79mA     4.442mA    4.643mA
-720mV    4.584mA    4.436mA    4.4mA
-412mV    3.306mA    3.179mA    3.213mA
316mV     -2.722mA   -2.615mA   -2.722mA
344mV     -2.963mA   -3.297mA   -2.965mA
372mV     -3.203mA   -3.514mA   -3.208mA
400mV     -3.965mA   -3.728mA   -4.12mA
904mV     -7.295mA   -7.041mA   -7.38mA
1.38V     -9.475mA   -9.236mA   -9.382mA
1.66V     -9.522mA   -9.376mA   -9.209mA
1.8V      -9.391mA   -8.672mA   -9.112mA
[GND_clamp]
|Voltage   I(typ)   I(min)   I(max)
-900mV    -26.23mA   -26.42mA   -31.01mA
-862mV    -22.92mA   -22.36mA   -27.37mA
-805mV    -18.34mA   -17.59mA   -22.08mA
-729mV    -12.72mA   -12.41mA   -15.41mA
-653mV    -7.804mA   -8.056mA   -9.454mA
-596mV    -4.802mA   -5.365mA   -5.752mA
-558mV    -3.209mA   -3.878mA   -3.771mA
-520mV    -1.991mA   -2.661mA   -2.259mA
-482mV    -1.164mA   -1.727mA   -1.259mA
-406mV    -478.8uA   -668.8uA   -533.3uA
-273mV    -266uA     -238.6uA   -325.5uA
900mV     -290.6nA   1.13uA     -22.03uA
[POWER_clamp]
|Voltage   I(typ)   I(min)   I(max)
-886mV    14.08mA    19.3mA     16.11mA
-867mV    12.88mA    16.46mA    15.27mA
-829mV    11.06mA    12.36mA    13.71mA
-753mV    8.386mA    7.879mA    10.81mA
-620mV    4.627mA    4.114mA    6.183mA
-430mV    1.011mA    1.102mA    1.355mA
-354mV    411uA      505.3uA    502.8uA
-221mV    159.2uA    144.5uA    192.7uA
368mV     0A         343.5uA    0A
387mV     431.3uA    334.2uA    0A
406mV     418.8uA    324.3uA    563.7uA
900mV     0A         0A         34.92uA
[Ramp]
| variable   typ   min   max
dV/dt_r   0.162/0.162n   0.152/0.182n   0.168/0.151n
dV/dt_f   0.170/0.143n   0.166/0.167n   0.169/0.131n
R_load = 50.000
[Rising Waveform]
R_fixture= 50.000
V_fixture= 0.0
V_fixture_min= 0.0
V_fixture_max= 0.0
|time   V(typ)   V(min)   V(max)
0s        1.599uV    8.537uV    733nV
392ps     232.9uV    125.4uV    2.295mV
500ps     5.337mV    -101.8uV   135.7mV
584ps     100.2mV    954.2uV    218.2mV
711ps     216.7mV    113.5mV    263.6mV
795ps     246.7mV    183.4mV    272.9mV
876ps     259.4mV    219.6mV    276.7mV
1.035ns   267.5mV    245.6mV    278.9mV
1.366ns   269.6mV    253.4mV    279.5mV
10ns      269.8mV    254mV      279.5mV
[Rising Waveform]
R_fixture= 50.000
V_fixture= 0.900
V_fixture_min= 0.870
V_fixture_max= 0.930
|time   V(typ)   V(min)   V(max)
0s        616.9mV    594.2mV    648mV
413ps     617mV      594.3mV    653.3mV
455ps     617.9mV    594.3mV    687.7mV
498ps     630.2mV    594.2mV    764.7mV
575ps     700.4mV    601.1mV    865.6mV
688ps     843.4mV    695.7mV    912.9mV
765ps     876.1mV    790.5mV    922.8mV
858ps     891.2mV    840.5mV    927.4mV
1.307ns   899.9mV    869.5mV    930mV
10ns      900mV      870mV      930mV
[Falling Waveform]
R_fixture= 50.000
V_fixture= 0.900
V_fixture_min= 0.870
V_fixture_max= 0.930
|time   V(typ)   V(min)   V(max)
0s        900mV      870mV      930mV
399ps     899.9mV    870mV      930mV
506ps     892.3mV    870.4mV    768.8mV
589ps     774.5mV    867.9mV    696.6mV
694ps     670.5mV    760.7mV    664.2mV
774ps     641.2mV    677.3mV    655.3mV
866ps     627.3mV    630.5mV    651.1mV
1.047ns   619.3mV    602.8mV    648.7mV
1.433ns   617.1mV    595mV      648.1mV
10ns      616.9mV    594.2mV    648mV
[Falling Waveform]
R_fixture= 50.000
V_fixture= 0.0
V_fixture_min= 0.0
V_fixture_max= 0.0
|time   V(typ)   V(min)   V(max)
0s        269.8mV    254mV      279.5mV
394ps     270.1mV    254mV      278.4mV
423ps     270.6mV    254.1mV    248.7mV
497ps     261.3mV    255mV      113.6mV
574ps     148.3mV    251mV      44.22mV
674ps     45.25mV    145.4mV    14.1mV
746ps     20.13mV    67.75mV    6.464mV
827ps     8.542mV    27.57mV    2.789mV
1.287ns   186uV      544.6uV    73.56uV
10ns      1.59uV     8.533uV    727.4nV
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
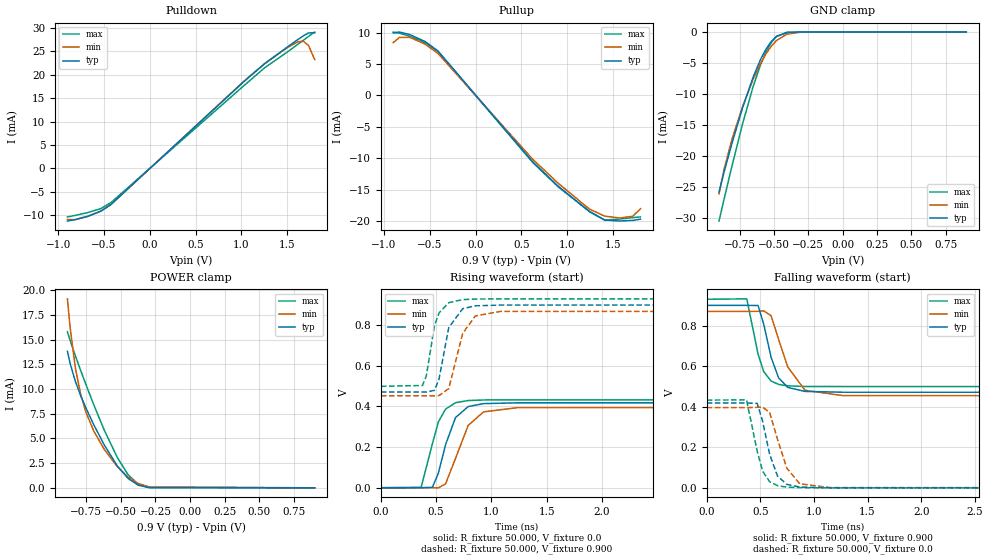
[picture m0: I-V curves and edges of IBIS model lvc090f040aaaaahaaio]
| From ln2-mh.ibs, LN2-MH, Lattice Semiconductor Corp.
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|   Model lvc090f040aaaaahaaio
[Model] lvc090f040aaaaahaaio
| Clamp models do not include dynamic input termination. Please refer to
| the lvc090axxxaaaaahaain model for input termination.
Model_type I/O
Polarity   Non-Inverting
Enable   Active-Low
Vinl =  0.300V
Vinh =  0.600V
Vmeas =  0.500V
Cref =  0.0F
Rref =  1.000M
Vref =  0.0V
C_comp   2.000pF   1.500pF   2.500pF
[Temperature Range]   25.000   0.125k   -40.000
[Voltage Range]   0.900V   0.870V   0.930V
[C Comp Corner]
C_comp   2.000pF   1.500pF   2.500pF
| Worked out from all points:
|   slope of the pulldown table from 0 to 0.135 V, typ, clamps not added: 54.8 ohm
|   slope of the pullup table from 0 to 0.135 V, typ, clamps not added: 55.9 ohm
|   GND clamp passes 1 mA (typ) near -0.50 V on its own axis
|   POWER clamp passes 1 mA (typ) near -0.45 V on its own axis
|   rising waveform, R_fixture 50.000, V_fixture 0.0: 20-80 % time 137ps typ, 167ps min, 121ps max; typ from 0 V to 0.418 V
|   rising waveform, R_fixture 50.000, V_fixture 0.900: 20-80 % time 98.4ps typ, 119ps min, 89.9ps max; typ from 0.471 V to 0.9 V
|   falling waveform, R_fixture 50.000, V_fixture 0.900: 20-80 % time 127ps typ, 168ps min, 107ps max; typ from 0.9 V to 0.471 V
|   falling waveform, R_fixture 50.000, V_fixture 0.0: 20-80 % time 117ps typ, 142ps min, 105ps max; typ from 0.418 V to 0 V
[Pulldown]
|Voltage   I(typ)   I(min)   I(max)
-900mV    -11.24mA   -10.92mA   -10.37mA
-816mV    -10.94mA   -10.96mA   -10.05mA
-676mV    -10.21mA   -10.25mA   -9.424mA
-536mV    -9.161mA   -9.109mA   -8.595mA
-424mV    -7.689mA   -7.698mA   -7.287mA
1.032V    18.6mA     18.7mA     17.74mA
1.256V    22.41mA    22.35mA    21.5mA
1.508V    25.99mA    25.86mA    24.93mA
1.62V     27.55mA    27.04mA    26.53mA
1.676V    28.29mA    27.12mA    27.34mA
1.732V    28.9mA     26.26mA    28.16mA
1.8V      28.95mA    23.22mA    29.1mA
[Pullup]
|Voltage   I(typ)   I(min)   I(max)
-900mV    9.971mA    8.423mA    10.08mA
-832mV    10.1mA     9.238mA    9.91mA
-720mV    9.7mA      9.259mA    9.435mA
-552mV    8.592mA    8.175mA    8.397mA
-412mV    7.089mA    6.707mA    7.025mA
624mV     -10.6mA    -10.18mA   -10.68mA
904mV     -14.49mA   -14.02mA   -14.59mA
1.24V     -18.48mA   -18.07mA   -18.43mA
1.408V    -19.85mA   -19.22mA   -19.84mA
1.576V    -20mA      -19.52mA   -19.69mA
1.716V    -19.9mA    -19.24mA   -19.46mA
1.8V      -19.7mA    -18.04mA   -19.35mA
[GND_clamp]
|Voltage   I(typ)   I(min)   I(max)
-900mV    -25.74mA   -26.04mA   -30.41mA
-862mV    -22.43mA   -21.97mA   -26.77mA
-805mV    -17.85mA   -17.2mA    -21.48mA
-729mV    -12.23mA   -12.01mA   -14.81mA
-653mV    -7.318mA   -7.665mA   -8.863mA
-596mV    -4.322mA   -4.979mA   -5.166mA
-558mV    -2.736mA   -3.498mA   -3.192mA
-520mV    -1.528mA   -2.289mA   -1.69mA
-482mV    -716.8uA   -1.366mA   -707.5uA
-406mV    -84.93uA   -343.7uA   -48.42uA
-311mV    -3.638uA   -36.43uA   -951.8nA
900mV     -18.6pA    0A         -12pA
[POWER_clamp]
|Voltage   I(typ)   I(min)   I(max)
-886mV    13.81mA    19.12mA    15.79mA
-867mV    12.61mA    16.27mA    14.94mA
-829mV    10.78mA    12.15mA    13.38mA
-791mV    9.351mA    9.485mA    11.9mA
-753mV    8.099mA    7.665mA    10.48mA
-696mV    6.388mA    5.752mA    8.409mA
-620mV    4.338mA    3.895mA    5.839mA
-525mV    2.205mA    2.133mA    3.051mA
-449mV    967uA      1.099mA    1.349mA
-373mV    256.9uA    426.8uA    331.7uA
-297mV    30.15uA    106.2uA    25.19uA
900mV     0A         0A         0A
[Ramp]
| variable   typ   min   max
dV/dt_r   0.251/0.137n   0.237/0.167n   0.260/0.121n
dV/dt_f   0.257/0.128n   0.250/0.169n   0.258/0.107n
R_load = 50.000
[Rising Waveform]
R_fixture= 50.000
V_fixture= 0.0
V_fixture_min= 0.0
V_fixture_max= 0.0
|time   V(typ)   V(min)   V(max)
0s        1.176uV    6.304uV    543.6nV
364ps     77.32uV    60.14uV    1.824mV
466ps     1.924mV    -184uV     216.4mV
520ps     71.39mV    -596.3uV   324mV
585ps     211.6mV    19.08mV    387mV
675ps     345.5mV    144.1mV    418.6mV
790ps     399.7mV    307mV      429.4mV
929ps     414.2mV    373.5mV    432.1mV
1.23ns    418mV      394mV      432.8mV
10ns      418.3mV    395.7mV    432.9mV
[Rising Waveform]
R_fixture= 50.000
V_fixture= 0.900
V_fixture_min= 0.870
V_fixture_max= 0.930
|time   V(typ)   V(min)   V(max)
0s        471.4mV    453mV      499.4mV
376ps     471.4mV    453mV      503.5mV
411ps     471.1mV    453mV      549.9mV
485ps     479.5mV    452.7mV    797.8mV
526ps     535.4mV    453.5mV    860.8mV
614ps     788.5mV    488.1mV    911.3mV
740ps     881.7mV    759.8mV    926.4mV
854ps     895.7mV    845.8mV    929mV
1.079ns   899.4mV    868mV      929.9mV
10ns      900mV      870mV      930mV
[Falling Waveform]
R_fixture= 50.000
V_fixture= 0.900
V_fixture_min= 0.870
V_fixture_max= 0.930
|time   V(typ)   V(min)   V(max)
0s        900mV      870mV      930mV
374ps     899.9mV    870mV      932mV
479ps     899.3mV    870.7mV    659.9mV
532ps     806.9mV    873mV      573.2mV
601ps     643.3mV    848.7mV    526.8mV
671ps     542mV      732mV      510mV
757ps     495.3mV    595.6mV    503mV
917ps     475.5mV    481.2mV    500mV
1.268ns   471.6mV    455mV      499.5mV
10ns      471.4mV    453mV      499.4mV
[Falling Waveform]
R_fixture= 50.000
V_fixture= 0.0
V_fixture_min= 0.0
V_fixture_max= 0.0
|time   V(typ)   V(min)   V(max)
0s        418.3mV    395.7mV    432.9mV
372ps     418.6mV    395.7mV    433.7mV
471ps     416.5mV    397.1mV    180.9mV
521ps     330mV      398.2mV    82.93mV
587ps     166.2mV    372.2mV    30.42mV
661ps     57.63mV    238.6mV    10.82mV
748ps     16.92mV    96.27mV    3.572mV
868ps     3.982mV    19.98mV    877.6uV
1.151ns   276.5uV    1.27mV     69.3uV
10ns      1.173uV    6.31uV     542nV
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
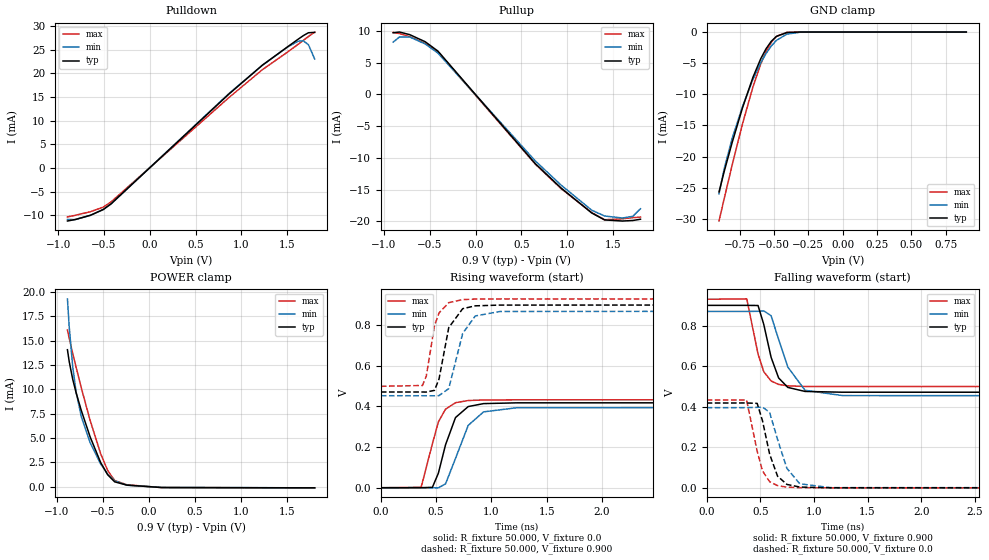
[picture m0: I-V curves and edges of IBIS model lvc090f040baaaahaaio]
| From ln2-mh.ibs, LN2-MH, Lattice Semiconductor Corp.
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|   Model lvc090f040baaaahaaio
[Model] lvc090f040baaaahaaio
| Clamp models do not include dynamic input termination. Please refer to
| the lvc090axxxbaaaahaain model for input termination.
Model_type I/O
Polarity   Non-Inverting
Enable   Active-Low
Vinl =  0.300V
Vinh =  0.600V
Vmeas =  0.500V
Cref =  0.0F
Rref =  1.000M
Vref =  0.0V
C_comp   2.000pF   1.500pF   2.500pF
[Temperature Range]   25.000   0.125k   -40.000
[Voltage Range]   0.900V   0.870V   0.930V
[C Comp Corner]
C_comp   2.000pF   1.500pF   2.500pF
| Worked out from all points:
|   slope of the pulldown table from 0 to 0.135 V, typ, clamps not added: 54.8 ohm
|   slope of the pullup table from 0 to 0.135 V, typ, clamps not added: 57.6 ohm
|   GND clamp passes 1 mA (typ) near -0.50 V on its own axis
|   POWER clamp passes 1 mA (typ) near -0.43 V on its own axis
|   rising waveform, R_fixture 50.000, V_fixture 0.0: 20-80 % time 137ps typ, 167ps min, 121ps max; typ from 0 V to 0.418 V
|   rising waveform, R_fixture 50.000, V_fixture 0.900: 20-80 % time 98.4ps typ, 119ps min, 89.9ps max; typ from 0.471 V to 0.9 V
|   falling waveform, R_fixture 50.000, V_fixture 0.900: 20-80 % time 127ps typ, 168ps min, 107ps max; typ from 0.9 V to 0.471 V
|   falling waveform, R_fixture 50.000, V_fixture 0.0: 20-80 % time 117ps typ, 142ps min, 105ps max; typ from 0.418 V to 0 V
[Pulldown]
|Voltage   I(typ)   I(min)   I(max)
-900mV    -11.22mA   -10.89mA   -10.35mA
-816mV    -10.91mA   -10.93mA   -10.02mA
-648mV    -9.994mA   -10.02mA   -9.246mA
-508mV    -8.789mA   -8.742mA   -8.275mA
-424mV    -7.591mA   -7.609mA   -7.186mA
864mV     15.65mA    15.76mA    14.91mA
1.228V    21.74mA    21.74mA    20.79mA
1.508V    25.7mA     25.64mA    24.59mA
1.62V     27.26mA    26.83mA    26.19mA
1.676V    28.01mA    26.92mA    27mA
1.732V    28.62mA    26.07mA    27.82mA
1.8V      28.69mA    23.06mA    28.77mA
[Pullup]
|Voltage   I(typ)   I(min)   I(max)
-900mV    9.705mA    8.245mA    9.756mA
-832mV    9.823mA    9.036mA    9.579mA
-720mV    9.411mA    9.042mA    9.096mA
-552mV    8.303mA    7.957mA    8.053mA
-412mV    6.82mA     6.504mA    6.697mA
652mV     -10.92mA   -10.49mA   -11mA
932mV     -14.74mA   -14.28mA   -14.84mA
1.268V    -18.69mA   -18.25mA   -18.62mA
1.408V    -19.78mA   -19.16mA   -19.75mA
1.604V    -19.95mA   -19.48mA   -19.6mA
1.716V    -19.87mA   -19.21mA   -19.43mA
1.8V      -19.67mA   -18.02mA   -19.33mA
[GND_clamp]
|Voltage   I(typ)   I(min)   I(max)
-900mV    -25.66mA   -25.96mA   -30.33mA
-862mV    -22.35mA   -21.9mA    -26.69mA
-805mV    -17.77mA   -17.12mA   -21.41mA
-729mV    -12.16mA   -11.94mA   -14.74mA
-653mV    -7.257mA   -7.604mA   -8.799mA
-596mV    -4.271mA   -4.926mA   -5.112mA
-558mV    -2.694mA   -3.451mA   -3.147mA
-520mV    -1.497mA   -2.251mA   -1.658mA
-482mV    -698.8uA   -1.337mA   -690.4uA
-406mV    -81.99uA   -333.1uA   -46.84uA
-311mV    -3.383uA   -34.47uA   -862nA
900mV     0A         0A         0A
[POWER_clamp]
|Voltage   I(typ)   I(min)   I(max)
-886mV    14.08mA    19.3mA     16.11mA
-867mV    12.88mA    16.46mA    15.27mA
-829mV    11.06mA    12.36mA    13.71mA
-791mV    9.635mA    9.695mA    12.24mA
-734mV    7.799mA    7.164mA    10.11mA
-639mV    5.115mA    4.532mA    6.802mA
-525mV    2.491mA    2.349mA    3.394mA
-449mV    1.244mA    1.308mA    1.684mA
-373mV    512.9uA    621.3uA    645.6uA
-240mV    175.8uA    166.1uA    212uA
140mV     -71.31uA   -61.44uA   -81.07uA
1.8V      -102.7uA   -103uA     -104uA
[Ramp]
| variable   typ   min   max
dV/dt_r   0.251/0.137n   0.237/0.167n   0.260/0.121n
dV/dt_f   0.257/0.128n   0.250/0.169n   0.258/0.107n
R_load = 50.000
[Rising Waveform]
R_fixture= 50.000
V_fixture= 0.0
V_fixture_min= 0.0
V_fixture_max= 0.0
|time   V(typ)   V(min)   V(max)
0s        1.176uV    6.304uV    543.6nV
364ps     77.32uV    60.14uV    1.824mV
466ps     1.924mV    -184uV     216.4mV
520ps     71.39mV    -596.3uV   324mV
585ps     211.6mV    19.08mV    387mV
675ps     345.5mV    144.1mV    418.6mV
790ps     399.7mV    307mV      429.4mV
929ps     414.2mV    373.5mV    432.1mV
1.23ns    418mV      394mV      432.8mV
10ns      418.3mV    395.7mV    432.9mV
[Rising Waveform]
R_fixture= 50.000
V_fixture= 0.900
V_fixture_min= 0.870
V_fixture_max= 0.930
|time   V(typ)   V(min)   V(max)
0s        471.4mV    453mV      499.4mV
376ps     471.4mV    453mV      503.5mV
411ps     471.1mV    453mV      549.9mV
485ps     479.5mV    452.7mV    797.8mV
526ps     535.4mV    453.5mV    860.8mV
614ps     788.5mV    488.1mV    911.3mV
740ps     881.7mV    759.8mV    926.4mV
854ps     895.7mV    845.8mV    929mV
1.079ns   899.4mV    868mV      929.9mV
10ns      900mV      870mV      930mV
[Falling Waveform]
R_fixture= 50.000
V_fixture= 0.900
V_fixture_min= 0.870
V_fixture_max= 0.930
|time   V(typ)   V(min)   V(max)
0s        900mV      870mV      930mV
374ps     899.9mV    870mV      932mV
479ps     899.3mV    870.7mV    659.9mV
532ps     806.9mV    873mV      573.2mV
601ps     643.3mV    848.7mV    526.8mV
671ps     542mV      732mV      510mV
757ps     495.3mV    595.6mV    503mV
917ps     475.5mV    481.2mV    500mV
1.268ns   471.6mV    455mV      499.5mV
10ns      471.4mV    453mV      499.4mV
[Falling Waveform]
R_fixture= 50.000
V_fixture= 0.0
V_fixture_min= 0.0
V_fixture_max= 0.0
|time   V(typ)   V(min)   V(max)
0s        418.3mV    395.7mV    432.9mV
372ps     418.6mV    395.7mV    433.7mV
471ps     416.5mV    397.1mV    180.9mV
521ps     330mV      398.2mV    82.93mV
587ps     166.2mV    372.2mV    30.42mV
661ps     57.63mV    238.6mV    10.82mV
748ps     16.92mV    96.27mV    3.572mV
868ps     3.982mV    19.98mV    877.6uV
1.151ns   276.5uV    1.27mV     69.3uV
10ns      1.173uV    6.31uV     542nV
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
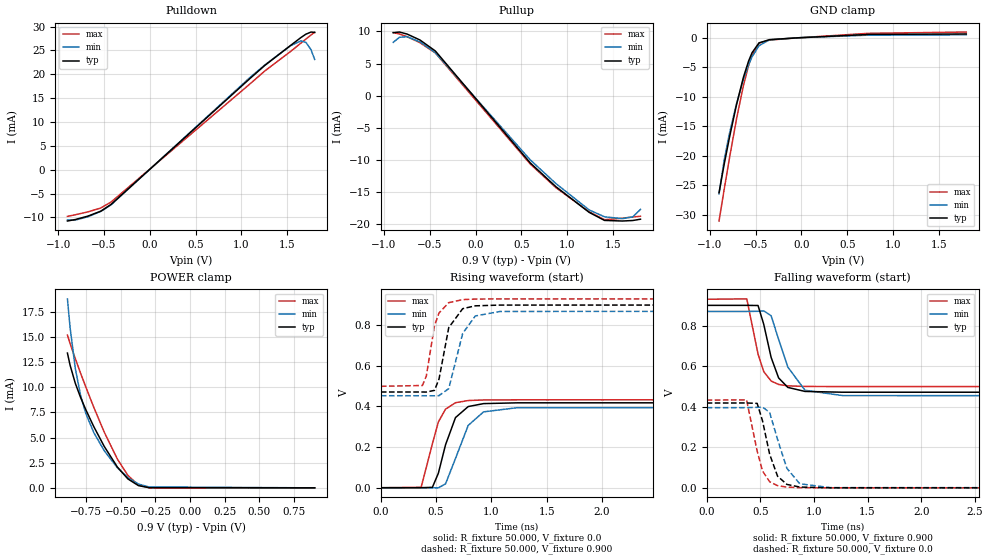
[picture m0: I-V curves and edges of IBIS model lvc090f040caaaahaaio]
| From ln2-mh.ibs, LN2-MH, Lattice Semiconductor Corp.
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|   Model lvc090f040caaaahaaio
[Model] lvc090f040caaaahaaio
| Clamp models do not include dynamic input termination. Please refer to
| the lvc090axxxcaaaahaain model for input termination.
Model_type I/O
Polarity   Non-Inverting
Enable   Active-Low
Vinl =  0.300V
Vinh =  0.600V
Vmeas =  0.500V
Cref =  0.0F
Rref =  1.000M
Vref =  0.0V
C_comp   2.000pF   1.500pF   2.500pF
[Temperature Range]   25.000   0.125k   -40.000
[Voltage Range]   0.900V   0.870V   0.930V
[C Comp Corner]
C_comp   2.000pF   1.500pF   2.500pF
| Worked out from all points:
|   slope of the pulldown table from 0 to 0.135 V, typ, clamps not added: 57.8 ohm
|   slope of the pullup table from 0 to 0.135 V, typ, clamps not added: 56.3 ohm
|   GND clamp passes 1 mA (typ) near -0.47 V on its own axis
|   POWER clamp passes 1 mA (typ) near -0.46 V on its own axis
|   rising waveform, R_fixture 50.000, V_fixture 0.0: 20-80 % time 137ps typ, 167ps min, 121ps max; typ from 0 V to 0.418 V
|   rising waveform, R_fixture 50.000, V_fixture 0.900: 20-80 % time 98.4ps typ, 119ps min, 89.9ps max; typ from 0.471 V to 0.9 V
|   falling waveform, R_fixture 50.000, V_fixture 0.900: 20-80 % time 127ps typ, 168ps min, 107ps max; typ from 0.9 V to 0.471 V
|   falling waveform, R_fixture 50.000, V_fixture 0.0: 20-80 % time 117ps typ, 142ps min, 105ps max; typ from 0.418 V to 0 V
[Pulldown]
|Voltage   I(typ)   I(min)   I(max)
-900mV    -10.75mA   -10.54mA   -9.775mA
-816mV    -10.45mA   -10.57mA   -9.448mA
-676mV    -9.72mA    -9.855mA   -8.831mA
-536mV    -8.693mA   -8.733mA   -8.021mA
-424mV    -7.279mA   -7.362mA   -6.782mA
1.088V    19.03mA    19.24mA    17.9mA
1.256V    21.87mA    21.97mA    20.71mA
1.536V    26.04mA    25.99mA    24.78mA
1.648V    27.68mA    26.99mA    26.51mA
1.704V    28.41mA    26.71mA    27.38mA
1.76V     28.86mA    25.14mA    28.24mA
1.8V      28.78mA    23.11mA    28.82mA
[Pullup]
|Voltage   I(typ)   I(min)   I(max)
-900mV    9.8mA      8.301mA    9.818mA
-832mV    9.902mA    9.089mA    9.597mA
-748mV    9.582mA    9.168mA    9.17mA
-608mV    8.661mA    8.366mA    8.248mA
-440mV    6.952mA    6.691mA    6.645mA
596mV     -10.45mA   -9.976mA   -10.62mA
876mV     -14.15mA   -13.66mA   -14.3mA
1.24V     -18.15mA   -17.77mA   -18.06mA
1.408V    -19.4mA    -18.84mA   -19.29mA
1.604V    -19.49mA   -19.12mA   -19.05mA
1.716V    -19.41mA   -18.84mA   -18.86mA
1.8V      -19.21mA   -17.68mA   -18.75mA
[GND_clamp]
|Voltage   I(typ)   I(min)   I(max)
-900mV    -26.23mA   -26.42mA   -31.01mA
-843mV    -21.35mA   -20.64mA   -25.59mA
-786mV    -16.88mA   -16.2mA    -20.37mA
-710mV    -11.41mA   -11.24mA   -13.83mA
-634mV    -6.729mA   -7.102mA   -8.134mA
-577mV    -3.961mA   -4.589mA   -4.707mA
-539mV    -2.551mA   -3.235mA   -2.953mA
-463mV    -890.5uA   -1.367mA   -946.5uA
-349mV    -352.6uA   -378.2uA   -421.6uA
-45mV     -42.8uA    -36.37uA   -52.77uA
734mV     527.5uA    410.9uA    719.1uA
1.8V      610uA      464.4uA    937.2uA
[POWER_clamp]
|Voltage   I(typ)   I(min)   I(max)
-886mV    13.4mA     18.79mA    15.19mA
-867mV    12.2mA     15.95mA    14.36mA
-829mV    10.39mA    11.85mA    12.84mA
-791mV    8.986mA    9.193mA    11.4mA
-753mV    7.76mA     7.389mA    10.02mA
-696mV    6.096mA    5.502mA    8.018mA
-620mV    4.114mA    3.69mA     5.536mA
-525mV    2.063mA    1.993mA    2.854mA
-449mV    884.5uA    1.009mA    1.231mA
-373mV    221.5uA    379.3uA    279.5uA
-297mV    19.57uA    87.58uA    7.748uA
900mV     0A         0A         0A
[Ramp]
| variable   typ   min   max
dV/dt_r   0.251/0.137n   0.237/0.167n   0.260/0.121n
dV/dt_f   0.257/0.128n   0.250/0.169n   0.258/0.107n
R_load = 50.000
[Rising Waveform]
R_fixture= 50.000
V_fixture= 0.0
V_fixture_min= 0.0
V_fixture_max= 0.0
|time   V(typ)   V(min)   V(max)
0s        1.176uV    6.304uV    543.6nV
364ps     77.32uV    60.14uV    1.824mV
466ps     1.924mV    -184uV     216.4mV
520ps     71.39mV    -596.3uV   324mV
585ps     211.6mV    19.08mV    387mV
675ps     345.5mV    144.1mV    418.6mV
790ps     399.7mV    307mV      429.4mV
929ps     414.2mV    373.5mV    432.1mV
1.23ns    418mV      394mV      432.8mV
10ns      418.3mV    395.7mV    432.9mV
[Rising Waveform]
R_fixture= 50.000
V_fixture= 0.900
V_fixture_min= 0.870
V_fixture_max= 0.930
|time   V(typ)   V(min)   V(max)
0s        471.4mV    453mV      499.4mV
376ps     471.4mV    453mV      503.5mV
411ps     471.1mV    453mV      549.9mV
485ps     479.5mV    452.7mV    797.8mV
526ps     535.4mV    453.5mV    860.8mV
614ps     788.5mV    488.1mV    911.3mV
740ps     881.7mV    759.8mV    926.4mV
854ps     895.7mV    845.8mV    929mV
1.079ns   899.4mV    868mV      929.9mV
10ns      900mV      870mV      930mV
[Falling Waveform]
R_fixture= 50.000
V_fixture= 0.900
V_fixture_min= 0.870
V_fixture_max= 0.930
|time   V(typ)   V(min)   V(max)
0s        900mV      870mV      930mV
374ps     899.9mV    870mV      932mV
479ps     899.3mV    870.7mV    659.9mV
532ps     806.9mV    873mV      573.2mV
601ps     643.3mV    848.7mV    526.8mV
671ps     542mV      732mV      510mV
757ps     495.3mV    595.6mV    503mV
917ps     475.5mV    481.2mV    500mV
1.268ns   471.6mV    455mV      499.5mV
10ns      471.4mV    453mV      499.4mV
[Falling Waveform]
R_fixture= 50.000
V_fixture= 0.0
V_fixture_min= 0.0
V_fixture_max= 0.0
|time   V(typ)   V(min)   V(max)
0s        418.3mV    395.7mV    432.9mV
372ps     418.6mV    395.7mV    433.7mV
471ps     416.5mV    397.1mV    180.9mV
521ps     330mV      398.2mV    82.93mV
587ps     166.2mV    372.2mV    30.42mV
661ps     57.63mV    238.6mV    10.82mV
748ps     16.92mV    96.27mV    3.572mV
868ps     3.982mV    19.98mV    877.6uV
1.151ns   276.5uV    1.27mV     69.3uV
10ns      1.173uV    6.31uV     542nV
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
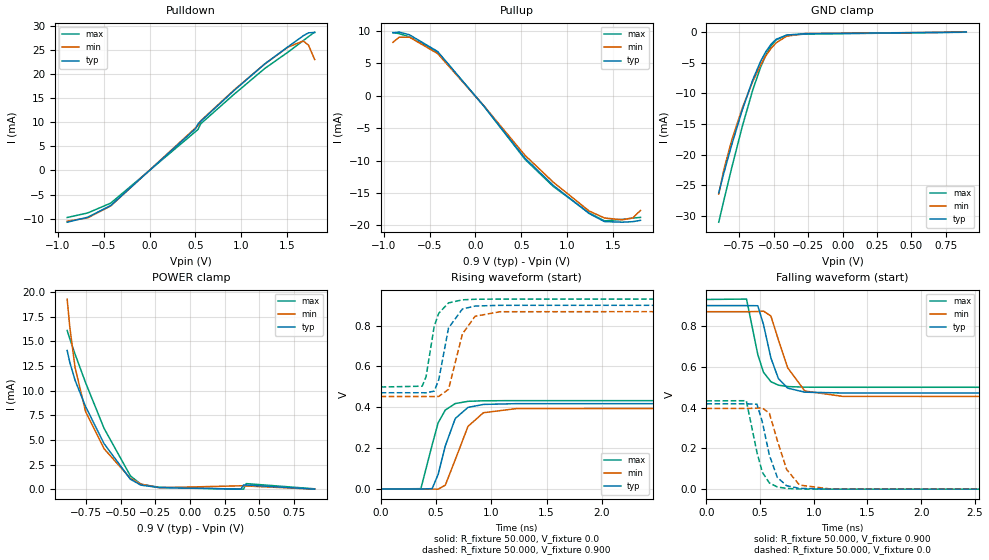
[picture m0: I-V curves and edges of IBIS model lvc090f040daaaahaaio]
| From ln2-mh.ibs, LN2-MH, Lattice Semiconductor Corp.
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|   Model lvc090f040daaaahaaio
[Model] lvc090f040daaaahaaio
| Clamp models do not include dynamic input termination. Please refer to
| the lvc090axxxdaaaahaain model for input termination.
Model_type I/O
Polarity   Non-Inverting
Enable   Active-Low
Vinl =  0.300V
Vinh =  0.600V
Vmeas =  0.500V
Cref =  0.0F
Rref =  1.000M
Vref =  0.0V
C_comp   2.000pF   1.500pF   2.500pF
[Temperature Range]   25.000   0.125k   -40.000
[Voltage Range]   0.900V   0.870V   0.930V
[C Comp Corner]
C_comp   2.000pF   1.500pF   2.500pF
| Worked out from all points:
|   slope of the pulldown table from 0 to 0.135 V, typ, clamps not added: 57.8 ohm
|   slope of the pullup table from 0 to 0.135 V, typ, clamps not added: 57.6 ohm
|   GND clamp passes 1 mA (typ) near -0.47 V on its own axis
|   POWER clamp passes 1 mA (typ) near -0.43 V on its own axis
|   rising waveform, R_fixture 50.000, V_fixture 0.0: 20-80 % time 137ps typ, 167ps min, 121ps max; typ from 0 V to 0.418 V
|   rising waveform, R_fixture 50.000, V_fixture 0.900: 20-80 % time 98.4ps typ, 119ps min, 89.9ps max; typ from 0.471 V to 0.9 V
|   falling waveform, R_fixture 50.000, V_fixture 0.900: 20-80 % time 127ps typ, 168ps min, 107ps max; typ from 0.9 V to 0.471 V
|   falling waveform, R_fixture 50.000, V_fixture 0.0: 20-80 % time 117ps typ, 142ps min, 105ps max; typ from 0.418 V to 0 V
[Pulldown]
|Voltage   I(typ)   I(min)   I(max)
-900mV    -10.75mA   -10.54mA   -9.775mA
-676mV    -9.72mA    -9.855mA   -8.831mA
-424mV    -7.279mA   -7.362mA   -6.782mA
500mV     8.668mA    8.857mA    8.081mA
528mV     9.697mA    9.353mA    8.537mA
556mV     10.2mA     10.31mA    9.688mA
920mV     16.61mA    16.72mA    15.83mA
1.256V    22.16mA    22.15mA    21.21mA
1.508V    25.7mA     25.64mA    24.59mA
1.676V    28.01mA    26.92mA    27mA
1.732V    28.62mA    26.07mA    27.82mA
1.8V      28.69mA    23.06mA    28.77mA
[Pullup]
|Voltage   I(typ)   I(min)   I(max)
-900mV    9.705mA    8.245mA    9.756mA
-832mV    9.823mA    9.036mA    9.579mA
-720mV    9.411mA    9.042mA    9.096mA
-412mV    6.82mA     6.504mA    6.697mA
92mV      -1.597mA   -1.544mA   -1.584mA
540mV     -9.62mA    -9.171mA   -9.788mA
848mV     -13.81mA   -13.31mA   -13.97mA
1.24V     -18.15mA   -17.77mA   -18.06mA
1.408V    -19.4mA    -18.84mA   -19.29mA
1.604V    -19.49mA   -19.12mA   -19.05mA
1.716V    -19.41mA   -18.84mA   -18.86mA
1.8V      -19.21mA   -17.68mA   -18.75mA
[GND_clamp]
|Voltage   I(typ)   I(min)   I(max)
-900mV    -26.23mA   -26.42mA   -31.01mA
-862mV    -22.92mA   -22.36mA   -27.37mA
-805mV    -18.34mA   -17.59mA   -22.08mA
-729mV    -12.72mA   -12.41mA   -15.41mA
-653mV    -7.804mA   -8.056mA   -9.454mA
-596mV    -4.802mA   -5.365mA   -5.752mA
-558mV    -3.209mA   -3.878mA   -3.771mA
-520mV    -1.991mA   -2.661mA   -2.259mA
-482mV    -1.164mA   -1.727mA   -1.259mA
-406mV    -478.8uA   -668.8uA   -533.3uA
-273mV    -266uA     -238.6uA   -325.5uA
900mV     -290.6nA   1.13uA     -22.03uA
[POWER_clamp]
|Voltage   I(typ)   I(min)   I(max)
-886mV    14.08mA    19.3mA     16.11mA
-867mV    12.88mA    16.46mA    15.27mA
-829mV    11.06mA    12.36mA    13.71mA
-753mV    8.386mA    7.879mA    10.81mA
-620mV    4.627mA    4.114mA    6.183mA
-430mV    1.011mA    1.102mA    1.355mA
-354mV    411uA      505.3uA    502.8uA
-221mV    159.2uA    144.5uA    192.7uA
368mV     0A         343.5uA    0A
387mV     431.3uA    334.2uA    0A
406mV     418.8uA    324.3uA    563.7uA
900mV     0A         0A         34.92uA
[Ramp]
| variable   typ   min   max
dV/dt_r   0.251/0.137n   0.237/0.167n   0.260/0.121n
dV/dt_f   0.257/0.128n   0.250/0.169n   0.258/0.107n
R_load = 50.000
[Rising Waveform]
R_fixture= 50.000
V_fixture= 0.0
V_fixture_min= 0.0
V_fixture_max= 0.0
|time   V(typ)   V(min)   V(max)
0s        1.176uV    6.304uV    543.6nV
364ps     77.32uV    60.14uV    1.824mV
466ps     1.924mV    -184uV     216.4mV
520ps     71.39mV    -596.3uV   324mV
585ps     211.6mV    19.08mV    387mV
675ps     345.5mV    144.1mV    418.6mV
790ps     399.7mV    307mV      429.4mV
929ps     414.2mV    373.5mV    432.1mV
1.23ns    418mV      394mV      432.8mV
10ns      418.3mV    395.7mV    432.9mV
[Rising Waveform]
R_fixture= 50.000
V_fixture= 0.900
V_fixture_min= 0.870
V_fixture_max= 0.930
|time   V(typ)   V(min)   V(max)
0s        471.4mV    453mV      499.4mV
376ps     471.4mV    453mV      503.5mV
411ps     471.1mV    453mV      549.9mV
485ps     479.5mV    452.7mV    797.8mV
526ps     535.4mV    453.5mV    860.8mV
614ps     788.5mV    488.1mV    911.3mV
740ps     881.7mV    759.8mV    926.4mV
854ps     895.7mV    845.8mV    929mV
1.079ns   899.4mV    868mV      929.9mV
10ns      900mV      870mV      930mV
[Falling Waveform]
R_fixture= 50.000
V_fixture= 0.900
V_fixture_min= 0.870
V_fixture_max= 0.930
|time   V(typ)   V(min)   V(max)
0s        900mV      870mV      930mV
374ps     899.9mV    870mV      932mV
479ps     899.3mV    870.7mV    659.9mV
532ps     806.9mV    873mV      573.2mV
601ps     643.3mV    848.7mV    526.8mV
671ps     542mV      732mV      510mV
757ps     495.3mV    595.6mV    503mV
917ps     475.5mV    481.2mV    500mV
1.268ns   471.6mV    455mV      499.5mV
10ns      471.4mV    453mV      499.4mV
[Falling Waveform]
R_fixture= 50.000
V_fixture= 0.0
V_fixture_min= 0.0
V_fixture_max= 0.0
|time   V(typ)   V(min)   V(max)
0s        418.3mV    395.7mV    432.9mV
372ps     418.6mV    395.7mV    433.7mV
471ps     416.5mV    397.1mV    180.9mV
521ps     330mV      398.2mV    82.93mV
587ps     166.2mV    372.2mV    30.42mV
661ps     57.63mV    238.6mV    10.82mV
748ps     16.92mV    96.27mV    3.572mV
868ps     3.982mV    19.98mV    877.6uV
1.151ns   276.5uV    1.27mV     69.3uV
10ns      1.173uV    6.31uV     542nV
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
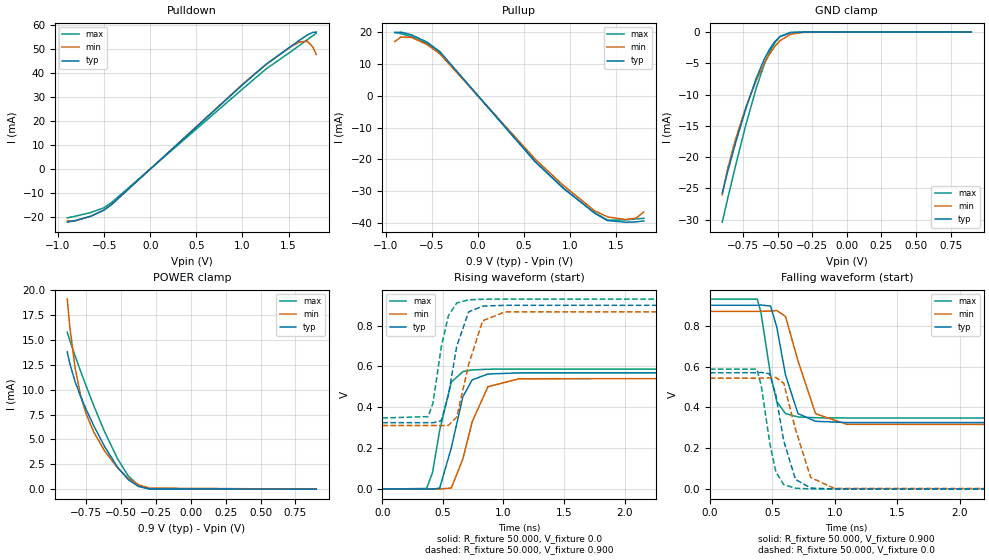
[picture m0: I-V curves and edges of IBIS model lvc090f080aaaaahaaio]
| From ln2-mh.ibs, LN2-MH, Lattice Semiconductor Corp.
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|   Model lvc090f080aaaaahaaio
[Model] lvc090f080aaaaahaaio
| Clamp models do not include dynamic input termination. Please refer to
| the lvc090axxxaaaaahaain model for input termination.
Model_type I/O
Polarity   Non-Inverting
Enable   Active-Low
Vinl =  0.300V
Vinh =  0.600V
Vmeas =  0.500V
Cref =  0.0F
Rref =  1.000M
Vref =  0.0V
C_comp   2.000pF   1.500pF   2.500pF
[Temperature Range]   25.000   0.125k   -40.000
[Voltage Range]   0.900V   0.870V   0.930V
[C Comp Corner]
C_comp   2.000pF   1.500pF   2.500pF
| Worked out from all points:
|   slope of the pulldown table from 0 to 0.135 V, typ, clamps not added: 28.2 ohm
|   slope of the pullup table from 0 to 0.135 V, typ, clamps not added: 28.7 ohm
|   GND clamp passes 1 mA (typ) near -0.50 V on its own axis
|   POWER clamp passes 1 mA (typ) near -0.45 V on its own axis
|   rising waveform, R_fixture 50.000, V_fixture 0.0: 20-80 % time 127ps typ, 153ps min, 110ps max; typ from 0 V to 0.569 V
|   rising waveform, R_fixture 50.000, V_fixture 0.900: 20-80 % time 110ps typ, 128ps min, 99.3ps max; typ from 0.325 V to 0.9 V
|   falling waveform, R_fixture 50.000, V_fixture 0.900: 20-80 % time 113ps typ, 144ps min, 95.3ps max; typ from 0.9 V to 0.325 V
|   falling waveform, R_fixture 50.000, V_fixture 0.0: 20-80 % time 109ps typ, 131ps min, 92.3ps max; typ from 0.569 V to 0 V
[Pulldown]
|Voltage   I(typ)   I(min)   I(max)
-900mV    -22.2mA    -21.68mA   -20.39mA
-816mV    -21.57mA   -21.64mA   -19.73mA
-648mV    -19.73mA   -19.78mA   -18.2mA
-508mV    -17.33mA   -17.24mA   -16.28mA
-424mV    -14.97mA   -15.01mA   -14.14mA
1.004V    35.22mA    35.47mA    33.47mA
1.256V    43.65mA    43.6mA     41.72mA
1.508V    50.69mA    50.55mA    48.47mA
1.62V     53.74mA    53.02mA    51.58mA
1.704V    55.9mA     53.22mA    53.95mA
1.76V     56.93mA    50.98mA    55.53mA
1.8V      57.08mA    47.78mA    56.61mA
[Pullup]
|Voltage   I(typ)   I(min)   I(max)
-900mV    19.84mA    17.02mA    19.88mA
-832mV    19.99mA    18.44mA    19.51mA
-720mV    19.14mA    18.34mA    18.55mA
-552mV    16.89mA    16.12mA    16.45mA
-412mV    13.87mA    13.18mA    13.7mA
624mV     -20.72mA   -19.97mA   -20.79mA
932mV     -29.11mA   -28.28mA   -29.23mA
1.268V    -36.95mA   -36.16mA   -36.75mA
1.408V    -39.23mA   -38.08mA   -39.12mA
1.604V    -39.74mA   -38.89mA   -39.02mA
1.716V    -39.64mA   -38.49mA   -38.71mA
1.8V      -39.33mA   -36.52mA   -38.52mA
[GND_clamp]
|Voltage   I(typ)   I(min)   I(max)
-900mV    -25.74mA   -26.04mA   -30.41mA
-862mV    -22.43mA   -21.97mA   -26.77mA
-805mV    -17.85mA   -17.2mA    -21.48mA
-729mV    -12.23mA   -12.01mA   -14.81mA
-653mV    -7.318mA   -7.665mA   -8.863mA
-596mV    -4.322mA   -4.979mA   -5.166mA
-558mV    -2.736mA   -3.498mA   -3.192mA
-520mV    -1.528mA   -2.289mA   -1.69mA
-482mV    -716.8uA   -1.366mA   -707.5uA
-406mV    -84.93uA   -343.7uA   -48.42uA
-311mV    -3.638uA   -36.43uA   -951.8nA
900mV     -18.59pA   0A         -11.95pA
[POWER_clamp]
|Voltage   I(typ)   I(min)   I(max)
-886mV    13.81mA    19.12mA    15.79mA
-867mV    12.61mA    16.27mA    14.94mA
-829mV    10.78mA    12.15mA    13.38mA
-791mV    9.351mA    9.485mA    11.9mA
-753mV    8.099mA    7.665mA    10.48mA
-696mV    6.388mA    5.752mA    8.409mA
-620mV    4.338mA    3.895mA    5.839mA
-525mV    2.205mA    2.133mA    3.051mA
-449mV    967uA      1.099mA    1.349mA
-373mV    256.9uA    426.8uA    331.7uA
-297mV    30.15uA    106.2uA    25.19uA
900mV     0A         0A         0A
[Ramp]
| variable   typ   min   max
dV/dt_r   0.342/0.127n   0.326/0.153n   0.352/0.110n
dV/dt_f   0.345/0.113n   0.335/0.145n   0.349/95.499p
R_load = 50.000
[Rising Waveform]
R_fixture= 50.000
V_fixture= 0.0
V_fixture_min= 0.0
V_fixture_max= 0.0
|time   V(typ)   V(min)   V(max)
0s        748.2nV    4.058uV    349.5nV
366ps     64.44uV    35.96uV    2.693mV
415ps     -583.3uV   68.41uV    81.1mV
474ps     4.821mV    -370.5uV   288mV
570ps     202mV      5.463mV    523.5mV
665ps     451.3mV    146.5mV    574.6mV
742ps     534.3mV    328.7mV    583.2mV
872ps     563mV      500.9mV    586.5mV
1.131ns   568.7mV    539.9mV    587.3mV
10ns      569.2mV    543mV      587.4mV
[Rising Waveform]
R_fixture= 50.000
V_fixture= 0.900
V_fixture_min= 0.870
V_fixture_max= 0.930
|time   V(typ)   V(min)   V(max)
0s        324.8mV    311.2mV    348mV
379ps     324.8mV    311.2mV    354.4mV
418ps     324.4mV    311.2mV    419.6mV
487ps     334.4mV    310.7mV    695.2mV
546ps     460.6mV    311.4mV    848.5mV
615ps     699.6mV    352.1mV    910.6mV
713ps     867mV      609.8mV    926.4mV
829ps     895.3mV    823.8mV    929.1mV
1.013ns   899.4mV    867.1mV    929.8mV
10ns      900mV      870mV      930mV
[Falling Waveform]
R_fixture= 50.000
V_fixture= 0.900
V_fixture_min= 0.870
V_fixture_max= 0.930
|time   V(typ)   V(min)   V(max)
0s        900mV      870mV      930mV
379ps     899.9mV    870mV      930.2mV
408ps     901.1mV    870mV      869.9mV
486ps     896.2mV    871.3mV    559.3mV
536ps     793.3mV    874mV      428.9mV
606ps     558mV      844.9mV    369.9mV
706ps     369.7mV    627.4mV    353.3mV
846ps     332.1mV    369.5mV    349.4mV
1.096ns   326mV      317.4mV    348.3mV
10ns      324.8mV    311.2mV    348mV
[Falling Waveform]
R_fixture= 50.000
V_fixture= 0.0
V_fixture_min= 0.0
V_fixture_max= 0.0
|time   V(typ)   V(min)   V(max)
0s        569.2mV    543mV      587.4mV
377ps     569.6mV    543mV      587.1mV
412ps     571.4mV    543.2mV    506.1mV
480ps     564.3mV    544.9mV    225mV
529ps     458.6mV    546.4mV    84.29mV
592ps     235.5mV    517.9mV    21.83mV
686ps     47.64mV    292.8mV    4.609mV
807ps     5.545mV    57.49mV    1.213mV
997ps     979.6uV    3.572mV    196.2uV
10ns      759.3nV    4.056uV    358.6nV
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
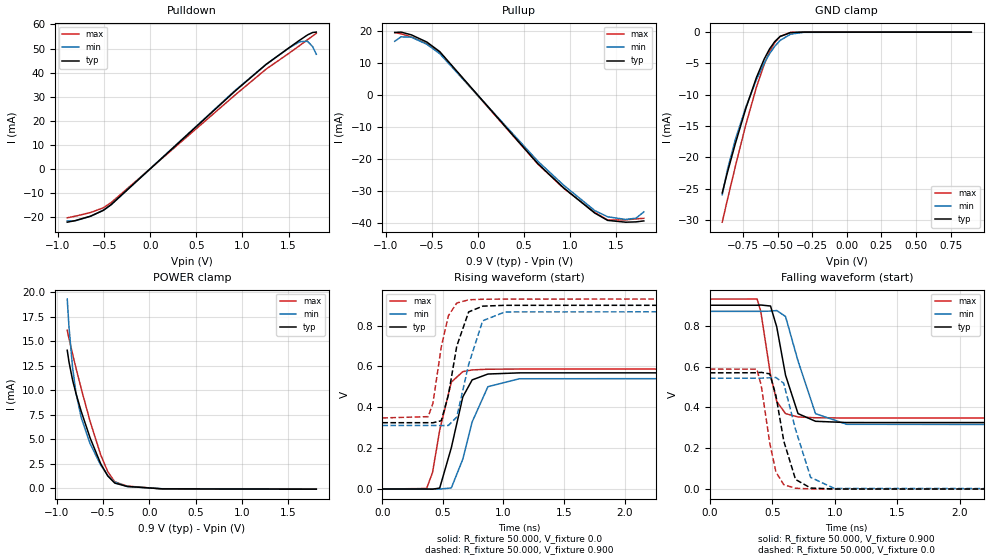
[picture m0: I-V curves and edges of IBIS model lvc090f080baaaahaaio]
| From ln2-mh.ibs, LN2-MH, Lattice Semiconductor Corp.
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|   Model lvc090f080baaaahaaio
[Model] lvc090f080baaaahaaio
| Clamp models do not include dynamic input termination. Please refer to
| the lvc090axxxbaaaahaain model for input termination.
Model_type I/O
Polarity   Non-Inverting
Enable   Active-Low
Vinl =  0.300V
Vinh =  0.600V
Vmeas =  0.500V
Cref =  0.0F
Rref =  1.000M
Vref =  0.0V
C_comp   2.000pF   1.500pF   2.500pF
[Temperature Range]   25.000   0.125k   -40.000
[Voltage Range]   0.900V   0.870V   0.930V
[C Comp Corner]
C_comp   2.000pF   1.500pF   2.500pF
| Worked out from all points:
|   slope of the pulldown table from 0 to 0.135 V, typ, clamps not added: 28.2 ohm
|   slope of the pullup table from 0 to 0.135 V, typ, clamps not added: 29.1 ohm
|   GND clamp passes 1 mA (typ) near -0.50 V on its own axis
|   POWER clamp passes 1 mA (typ) near -0.43 V on its own axis
|   rising waveform, R_fixture 50.000, V_fixture 0.0: 20-80 % time 127ps typ, 153ps min, 110ps max; typ from 0 V to 0.569 V
|   rising waveform, R_fixture 50.000, V_fixture 0.900: 20-80 % time 110ps typ, 128ps min, 99.3ps max; typ from 0.325 V to 0.9 V
|   falling waveform, R_fixture 50.000, V_fixture 0.900: 20-80 % time 113ps typ, 144ps min, 95.3ps max; typ from 0.9 V to 0.325 V
|   falling waveform, R_fixture 50.000, V_fixture 0.0: 20-80 % time 109ps typ, 131ps min, 92.3ps max; typ from 0.569 V to 0 V
[Pulldown]
|Voltage   I(typ)   I(min)   I(max)
-900mV    -22.17mA   -21.65mA   -20.36mA
-816mV    -21.54mA   -21.61mA   -19.7mA
-648mV    -19.68mA   -19.73mA   -18.16mA
-508mV    -17.25mA   -17.17mA   -16.2mA
-424mV    -14.87mA   -14.92mA   -14.04mA
920mV     32.32mA    32.58mA    30.69mA
1.256V    43.4mA     43.4mA     41.43mA
1.508V    50.4mA     50.34mA    48.13mA
1.62V     53.46mA    52.81mA    51.23mA
1.704V    55.62mA    53.02mA    53.61mA
1.76V     56.65mA    50.8mA     55.2mA
1.8V      56.82mA    47.62mA    56.29mA
[Pullup]
|Voltage   I(typ)   I(min)   I(max)
-900mV    19.57mA    16.84mA    19.56mA
-832mV    19.71mA    18.23mA    19.18mA
-720mV    18.85mA    18.12mA    18.21mA
-552mV    16.6mA     15.9mA     16.11mA
-412mV    13.6mA     12.97mA    13.37mA
652mV     -21.44mA   -20.67mA   -21.53mA
932mV     -29.01mA   -28.17mA   -29.13mA
1.268V    -36.85mA   -36.07mA   -36.65mA
1.408V    -39.15mA   -38.02mA   -39.03mA
1.604V    -39.71mA   -38.85mA   -38.98mA
1.716V    -39.61mA   -38.46mA   -38.68mA
1.8V      -39.31mA   -36.5mA    -38.5mA
[GND_clamp]
|Voltage   I(typ)   I(min)   I(max)
-900mV    -25.66mA   -25.96mA   -30.33mA
-862mV    -22.35mA   -21.9mA    -26.69mA
-805mV    -17.77mA   -17.12mA   -21.41mA
-729mV    -12.16mA   -11.94mA   -14.74mA
-653mV    -7.257mA   -7.604mA   -8.799mA
-596mV    -4.271mA   -4.926mA   -5.112mA
-558mV    -2.694mA   -3.451mA   -3.147mA
-520mV    -1.497mA   -2.251mA   -1.658mA
-482mV    -698.8uA   -1.337mA   -690.4uA
-406mV    -81.99uA   -333.1uA   -46.84uA
-311mV    -3.383uA   -34.47uA   -862nA
900mV     0A         0A         0A
[POWER_clamp]
|Voltage   I(typ)   I(min)   I(max)
-886mV    14.08mA    19.3mA     16.11mA
-867mV    12.88mA    16.46mA    15.27mA
-829mV    11.06mA    12.36mA    13.71mA
-791mV    9.635mA    9.695mA    12.24mA
-734mV    7.799mA    7.164mA    10.11mA
-639mV    5.115mA    4.532mA    6.802mA
-525mV    2.491mA    2.349mA    3.394mA
-449mV    1.244mA    1.308mA    1.684mA
-373mV    512.9uA    621.3uA    645.6uA
-240mV    175.8uA    166.1uA    212uA
140mV     -71.31uA   -61.44uA   -81.07uA
1.8V      -102.7uA   -103uA     -104uA
[Ramp]
| variable   typ   min   max
dV/dt_r   0.342/0.127n   0.326/0.153n   0.352/0.110n
dV/dt_f   0.345/0.113n   0.335/0.145n   0.349/95.499p
R_load = 50.000
[Rising Waveform]
R_fixture= 50.000
V_fixture= 0.0
V_fixture_min= 0.0
V_fixture_max= 0.0
|time   V(typ)   V(min)   V(max)
0s        748.2nV    4.058uV    349.5nV
366ps     64.44uV    35.96uV    2.693mV
415ps     -583.3uV   68.41uV    81.1mV
474ps     4.821mV    -370.5uV   288mV
570ps     202mV      5.463mV    523.5mV
665ps     451.3mV    146.5mV    574.6mV
742ps     534.3mV    328.7mV    583.2mV
872ps     563mV      500.9mV    586.5mV
1.131ns   568.7mV    539.9mV    587.3mV
10ns      569.2mV    543mV      587.4mV
[Rising Waveform]
R_fixture= 50.000
V_fixture= 0.900
V_fixture_min= 0.870
V_fixture_max= 0.930
|time   V(typ)   V(min)   V(max)
0s        324.8mV    311.2mV    348mV
379ps     324.8mV    311.2mV    354.4mV
418ps     324.4mV    311.2mV    419.6mV
487ps     334.4mV    310.7mV    695.2mV
546ps     460.6mV    311.4mV    848.5mV
615ps     699.6mV    352.1mV    910.6mV
713ps     867mV      609.8mV    926.4mV
829ps     895.3mV    823.8mV    929.1mV
1.013ns   899.4mV    867.1mV    929.8mV
10ns      900mV      870mV      930mV
[Falling Waveform]
R_fixture= 50.000
V_fixture= 0.900
V_fixture_min= 0.870
V_fixture_max= 0.930
|time   V(typ)   V(min)   V(max)
0s        900mV      870mV      930mV
379ps     899.9mV    870mV      930.2mV
408ps     901.1mV    870mV      869.9mV
486ps     896.2mV    871.3mV    559.3mV
536ps     793.3mV    874mV      428.9mV
606ps     558mV      844.9mV    369.9mV
706ps     369.7mV    627.4mV    353.3mV
846ps     332.1mV    369.5mV    349.4mV
1.096ns   326mV      317.4mV    348.3mV
10ns      324.8mV    311.2mV    348mV
[Falling Waveform]
R_fixture= 50.000
V_fixture= 0.0
V_fixture_min= 0.0
V_fixture_max= 0.0
|time   V(typ)   V(min)   V(max)
0s        569.2mV    543mV      587.4mV
377ps     569.6mV    543mV      587.1mV
412ps     571.4mV    543.2mV    506.1mV
480ps     564.3mV    544.9mV    225mV
529ps     458.6mV    546.4mV    84.29mV
592ps     235.5mV    517.9mV    21.83mV
686ps     47.64mV    292.8mV    4.609mV
807ps     5.545mV    57.49mV    1.213mV
997ps     979.6uV    3.572mV    196.2uV
10ns      759.3nV    4.056uV    358.6nV
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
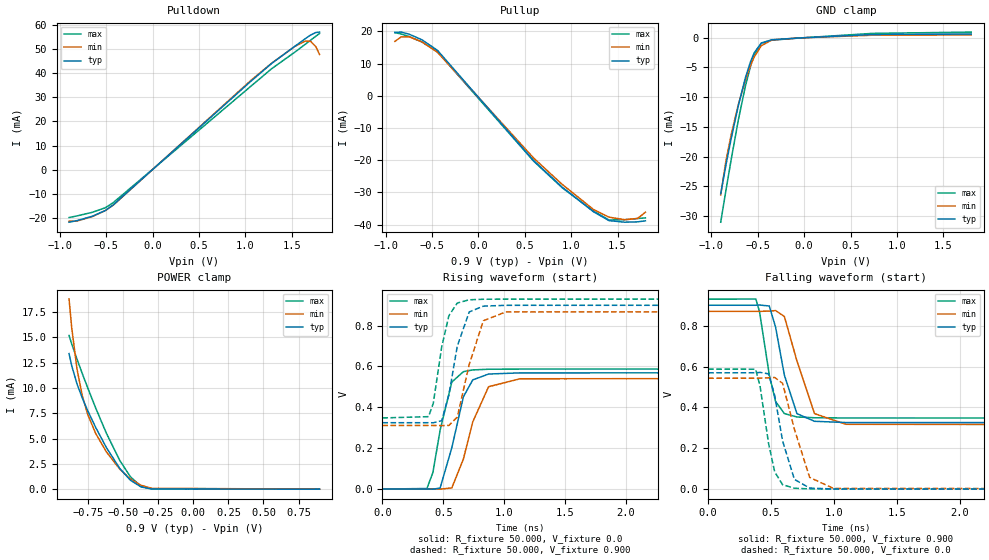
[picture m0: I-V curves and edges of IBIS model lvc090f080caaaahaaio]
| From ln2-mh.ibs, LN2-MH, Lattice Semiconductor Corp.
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|   Model lvc090f080caaaahaaio
[Model] lvc090f080caaaahaaio
| Clamp models do not include dynamic input termination. Please refer to
| the lvc090axxxcaaaahaain model for input termination.
Model_type I/O
Polarity   Non-Inverting
Enable   Active-Low
Vinl =  0.300V
Vinh =  0.600V
Vmeas =  0.500V
Cref =  0.0F
Rref =  1.000M
Vref =  0.0V
C_comp   2.000pF   1.500pF   2.500pF
[Temperature Range]   25.000   0.125k   -40.000
[Voltage Range]   0.900V   0.870V   0.930V
[C Comp Corner]
C_comp   2.000pF   1.500pF   2.500pF
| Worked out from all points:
|   slope of the pulldown table from 0 to 0.135 V, typ, clamps not added: 29 ohm
|   slope of the pullup table from 0 to 0.135 V, typ, clamps not added: 28.8 ohm
|   GND clamp passes 1 mA (typ) near -0.47 V on its own axis
|   POWER clamp passes 1 mA (typ) near -0.46 V on its own axis
|   rising waveform, R_fixture 50.000, V_fixture 0.0: 20-80 % time 127ps typ, 153ps min, 110ps max; typ from 0 V to 0.569 V
|   rising waveform, R_fixture 50.000, V_fixture 0.900: 20-80 % time 110ps typ, 128ps min, 99.3ps max; typ from 0.325 V to 0.9 V
|   falling waveform, R_fixture 50.000, V_fixture 0.900: 20-80 % time 113ps typ, 144ps min, 95.3ps max; typ from 0.9 V to 0.325 V
|   falling waveform, R_fixture 50.000, V_fixture 0.0: 20-80 % time 109ps typ, 131ps min, 92.3ps max; typ from 0.569 V to 0 V
[Pulldown]
|Voltage   I(typ)   I(min)   I(max)
-900mV    -21.71mA   -21.3mA    -19.79mA
-816mV    -21.07mA   -21.25mA   -19.13mA
-648mV    -19.24mA   -19.38mA   -17.61mA
-508mV    -16.87mA   -16.87mA   -15.72mA
-424mV    -14.56mA   -14.68mA   -13.63mA
1.06V     36.59mA    36.94mA    34.53mA
1.284V    43.96mA    44.05mA    41.77mA
1.536V    51.11mA    51.04mA    48.69mA
1.648V    54.24mA    53.2mA     51.93mA
1.704V    55.69mA    53.07mA    53.58mA
1.76V     56.74mA    50.86mA    55.21mA
1.8V      56.91mA    47.67mA    56.33mA
[Pullup]
|Voltage   I(typ)   I(min)   I(max)
-900mV    19.67mA    16.9mA     19.62mA
-832mV    19.79mA    18.29mA    19.2mA
-748mV    19.16mA    18.35mA    18.42mA
-608mV    17.4mA     16.76mA    16.71mA
-440mV    14.09mA    13.5mA     13.65mA
596mV     -20.15mA   -19.36mA   -20.31mA
904mV     -28.41mA   -27.54mA   -28.57mA
1.24V     -36.01mA   -35.3mA    -35.8mA
1.408V    -38.77mA   -37.7mA    -38.57mA
1.576V    -39.26mA   -38.47mA   -38.51mA
1.716V    -39.15mA   -38.1mA    -38.11mA
1.8V      -38.84mA   -36.16mA   -37.92mA
[GND_clamp]
|Voltage   I(typ)   I(min)   I(max)
-900mV    -26.23mA   -26.42mA   -31.01mA
-843mV    -21.35mA   -20.64mA   -25.59mA
-786mV    -16.88mA   -16.2mA    -20.37mA
-710mV    -11.41mA   -11.24mA   -13.83mA
-634mV    -6.729mA   -7.102mA   -8.134mA
-577mV    -3.961mA   -4.589mA   -4.707mA
-539mV    -2.551mA   -3.235mA   -2.953mA
-463mV    -890.5uA   -1.367mA   -946.5uA
-349mV    -352.6uA   -378.2uA   -421.6uA
-45mV     -42.8uA    -36.37uA   -52.77uA
734mV     527.5uA    410.9uA    719.1uA
1.8V      610uA      464.4uA    937.2uA
[POWER_clamp]
|Voltage   I(typ)   I(min)   I(max)
-886mV    13.4mA     18.79mA    15.19mA
-867mV    12.2mA     15.95mA    14.36mA
-829mV    10.39mA    11.85mA    12.84mA
-791mV    8.986mA    9.193mA    11.4mA
-753mV    7.76mA     7.389mA    10.02mA
-696mV    6.096mA    5.502mA    8.018mA
-620mV    4.114mA    3.69mA     5.536mA
-525mV    2.063mA    1.993mA    2.854mA
-449mV    884.5uA    1.009mA    1.231mA
-373mV    221.5uA    379.3uA    279.5uA
-297mV    19.57uA    87.58uA    7.748uA
900mV     0A         0A         0A
[Ramp]
| variable   typ   min   max
dV/dt_r   0.342/0.127n   0.326/0.153n   0.352/0.110n
dV/dt_f   0.345/0.113n   0.335/0.145n   0.349/95.499p
R_load = 50.000
[Rising Waveform]
R_fixture= 50.000
V_fixture= 0.0
V_fixture_min= 0.0
V_fixture_max= 0.0
|time   V(typ)   V(min)   V(max)
0s        748.2nV    4.058uV    349.5nV
366ps     64.44uV    35.96uV    2.693mV
415ps     -583.3uV   68.41uV    81.1mV
474ps     4.821mV    -370.5uV   288mV
570ps     202mV      5.463mV    523.5mV
665ps     451.3mV    146.5mV    574.6mV
742ps     534.3mV    328.7mV    583.2mV
872ps     563mV      500.9mV    586.5mV
1.131ns   568.7mV    539.9mV    587.3mV
10ns      569.2mV    543mV      587.4mV
[Rising Waveform]
R_fixture= 50.000
V_fixture= 0.900
V_fixture_min= 0.870
V_fixture_max= 0.930
|time   V(typ)   V(min)   V(max)
0s        324.8mV    311.2mV    348mV
379ps     324.8mV    311.2mV    354.4mV
418ps     324.4mV    311.2mV    419.6mV
487ps     334.4mV    310.7mV    695.2mV
546ps     460.6mV    311.4mV    848.5mV
615ps     699.6mV    352.1mV    910.6mV
713ps     867mV      609.8mV    926.4mV
829ps     895.3mV    823.8mV    929.1mV
1.013ns   899.4mV    867.1mV    929.8mV
10ns      900mV      870mV      930mV
[Falling Waveform]
R_fixture= 50.000
V_fixture= 0.900
V_fixture_min= 0.870
V_fixture_max= 0.930
|time   V(typ)   V(min)   V(max)
0s        900mV      870mV      930mV
379ps     899.9mV    870mV      930.2mV
408ps     901.1mV    870mV      869.9mV
486ps     896.2mV    871.3mV    559.3mV
536ps     793.3mV    874mV      428.9mV
606ps     558mV      844.9mV    369.9mV
706ps     369.7mV    627.4mV    353.3mV
846ps     332.1mV    369.5mV    349.4mV
1.096ns   326mV      317.4mV    348.3mV
10ns      324.8mV    311.2mV    348mV
[Falling Waveform]
R_fixture= 50.000
V_fixture= 0.0
V_fixture_min= 0.0
V_fixture_max= 0.0
|time   V(typ)   V(min)   V(max)
0s        569.2mV    543mV      587.4mV
377ps     569.6mV    543mV      587.1mV
412ps     571.4mV    543.2mV    506.1mV
480ps     564.3mV    544.9mV    225mV
529ps     458.6mV    546.4mV    84.29mV
592ps     235.5mV    517.9mV    21.83mV
686ps     47.64mV    292.8mV    4.609mV
807ps     5.545mV    57.49mV    1.213mV
997ps     979.6uV    3.572mV    196.2uV
10ns      759.3nV    4.056uV    358.6nV
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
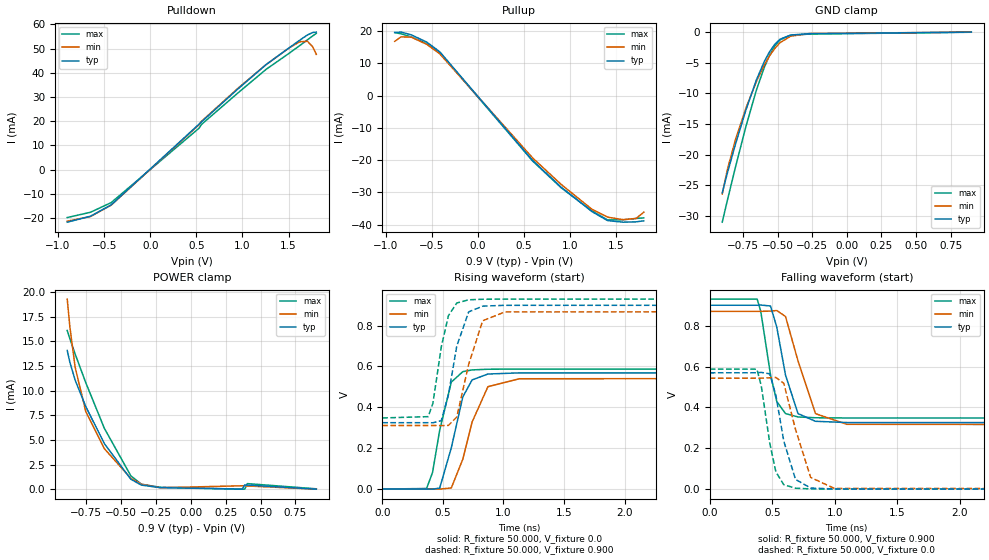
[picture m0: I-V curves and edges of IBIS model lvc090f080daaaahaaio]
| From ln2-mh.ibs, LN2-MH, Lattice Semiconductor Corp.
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|   Model lvc090f080daaaahaaio
[Model] lvc090f080daaaahaaio
| Clamp models do not include dynamic input termination. Please refer to
| the lvc090axxxdaaaahaain model for input termination.
Model_type I/O
Polarity   Non-Inverting
Enable   Active-Low
Vinl =  0.300V
Vinh =  0.600V
Vmeas =  0.500V
Cref =  0.0F
Rref =  1.000M
Vref =  0.0V
C_comp   2.000pF   1.500pF   2.500pF
[Temperature Range]   25.000   0.125k   -40.000
[Voltage Range]   0.900V   0.870V   0.930V
[C Comp Corner]
C_comp   2.000pF   1.500pF   2.500pF
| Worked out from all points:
|   slope of the pulldown table from 0 to 0.135 V, typ, clamps not added: 29 ohm
|   slope of the pullup table from 0 to 0.135 V, typ, clamps not added: 29.1 ohm
|   GND clamp passes 1 mA (typ) near -0.47 V on its own axis
|   POWER clamp passes 1 mA (typ) near -0.43 V on its own axis
|   rising waveform, R_fixture 50.000, V_fixture 0.0: 20-80 % time 127ps typ, 153ps min, 110ps max; typ from 0 V to 0.569 V
|   rising waveform, R_fixture 50.000, V_fixture 0.900: 20-80 % time 110ps typ, 128ps min, 99.3ps max; typ from 0.325 V to 0.9 V
|   falling waveform, R_fixture 50.000, V_fixture 0.900: 20-80 % time 113ps typ, 144ps min, 95.3ps max; typ from 0.9 V to 0.325 V
|   falling waveform, R_fixture 50.000, V_fixture 0.0: 20-80 % time 109ps typ, 131ps min, 92.3ps max; typ from 0.569 V to 0 V
[Pulldown]
|Voltage   I(typ)   I(min)   I(max)
-900mV    -21.71mA   -21.3mA    -19.79mA
-648mV    -19.24mA   -19.38mA   -17.61mA
-424mV    -14.56mA   -14.68mA   -13.63mA
528mV     18.76mA    18.54mA    17.08mA
556mV     19.75mA    19.98mA    18.69mA
948mV     33.26mA    33.52mA    31.6mA
1.256V    43.4mA     43.4mA     41.43mA
1.508V    50.4mA     50.34mA    48.13mA
1.62V     53.46mA    52.81mA    51.23mA
1.704V    55.62mA    53.02mA    53.61mA
1.76V     56.65mA    50.8mA     55.2mA
1.8V      56.82mA    47.62mA    56.29mA
[Pullup]
|Voltage   I(typ)   I(min)   I(max)
-900mV    19.57mA    16.84mA    19.56mA
-832mV    19.71mA    18.23mA    19.18mA
-720mV    18.85mA    18.12mA    18.21mA
-552mV    16.6mA     15.9mA     16.11mA
-412mV    13.6mA     12.97mA    13.37mA
596mV     -20.15mA   -19.36mA   -20.31mA
904mV     -28.41mA   -27.54mA   -28.57mA
1.24V     -36.01mA   -35.3mA    -35.8mA
1.408V    -38.77mA   -37.7mA    -38.57mA
1.576V    -39.26mA   -38.47mA   -38.51mA
1.716V    -39.15mA   -38.1mA    -38.11mA
1.8V      -38.84mA   -36.16mA   -37.92mA
[GND_clamp]
|Voltage   I(typ)   I(min)   I(max)
-900mV    -26.23mA   -26.42mA   -31.01mA
-862mV    -22.92mA   -22.36mA   -27.37mA
-805mV    -18.34mA   -17.59mA   -22.08mA
-729mV    -12.72mA   -12.41mA   -15.41mA
-653mV    -7.804mA   -8.056mA   -9.454mA
-596mV    -4.802mA   -5.365mA   -5.752mA
-558mV    -3.209mA   -3.878mA   -3.771mA
-520mV    -1.991mA   -2.661mA   -2.259mA
-482mV    -1.164mA   -1.727mA   -1.259mA
-406mV    -478.8uA   -668.8uA   -533.3uA
-273mV    -266uA     -238.6uA   -325.5uA
900mV     -290.6nA   1.13uA     -22.03uA
[POWER_clamp]
|Voltage   I(typ)   I(min)   I(max)
-886mV    14.08mA    19.3mA     16.11mA
-867mV    12.88mA    16.46mA    15.27mA
-829mV    11.06mA    12.36mA    13.71mA
-753mV    8.386mA    7.879mA    10.81mA
-620mV    4.627mA    4.114mA    6.183mA
-430mV    1.011mA    1.102mA    1.355mA
-354mV    411uA      505.3uA    502.8uA
-221mV    159.2uA    144.5uA    192.7uA
368mV     0A         343.5uA    0A
387mV     431.3uA    334.2uA    0A
406mV     418.8uA    324.3uA    563.7uA
900mV     0A         0A         34.92uA
[Ramp]
| variable   typ   min   max
dV/dt_r   0.342/0.127n   0.326/0.153n   0.352/0.110n
dV/dt_f   0.345/0.113n   0.335/0.145n   0.349/95.499p
R_load = 50.000
[Rising Waveform]
R_fixture= 50.000
V_fixture= 0.0
V_fixture_min= 0.0
V_fixture_max= 0.0
|time   V(typ)   V(min)   V(max)
0s        748.2nV    4.058uV    349.5nV
366ps     64.44uV    35.96uV    2.693mV
415ps     -583.3uV   68.41uV    81.1mV
474ps     4.821mV    -370.5uV   288mV
570ps     202mV      5.463mV    523.5mV
665ps     451.3mV    146.5mV    574.6mV
742ps     534.3mV    328.7mV    583.2mV
872ps     563mV      500.9mV    586.5mV
1.131ns   568.7mV    539.9mV    587.3mV
10ns      569.2mV    543mV      587.4mV
[Rising Waveform]
R_fixture= 50.000
V_fixture= 0.900
V_fixture_min= 0.870
V_fixture_max= 0.930
|time   V(typ)   V(min)   V(max)
0s        324.8mV    311.2mV    348mV
379ps     324.8mV    311.2mV    354.4mV
418ps     324.4mV    311.2mV    419.6mV
487ps     334.4mV    310.7mV    695.2mV
546ps     460.6mV    311.4mV    848.5mV
615ps     699.6mV    352.1mV    910.6mV
713ps     867mV      609.8mV    926.4mV
829ps     895.3mV    823.8mV    929.1mV
1.013ns   899.4mV    867.1mV    929.8mV
10ns      900mV      870mV      930mV
[Falling Waveform]
R_fixture= 50.000
V_fixture= 0.900
V_fixture_min= 0.870
V_fixture_max= 0.930
|time   V(typ)   V(min)   V(max)
0s        900mV      870mV      930mV
379ps     899.9mV    870mV      930.2mV
408ps     901.1mV    870mV      869.9mV
486ps     896.2mV    871.3mV    559.3mV
536ps     793.3mV    874mV      428.9mV
606ps     558mV      844.9mV    369.9mV
706ps     369.7mV    627.4mV    353.3mV
846ps     332.1mV    369.5mV    349.4mV
1.096ns   326mV      317.4mV    348.3mV
10ns      324.8mV    311.2mV    348mV
[Falling Waveform]
R_fixture= 50.000
V_fixture= 0.0
V_fixture_min= 0.0
V_fixture_max= 0.0
|time   V(typ)   V(min)   V(max)
0s        569.2mV    543mV      587.4mV
377ps     569.6mV    543mV      587.1mV
412ps     571.4mV    543.2mV    506.1mV
480ps     564.3mV    544.9mV    225mV
529ps     458.6mV    546.4mV    84.29mV
592ps     235.5mV    517.9mV    21.83mV
686ps     47.64mV    292.8mV    4.609mV
807ps     5.545mV    57.49mV    1.213mV
997ps     979.6uV    3.572mV    196.2uV
10ns      759.3nV    4.056uV    357.9nV
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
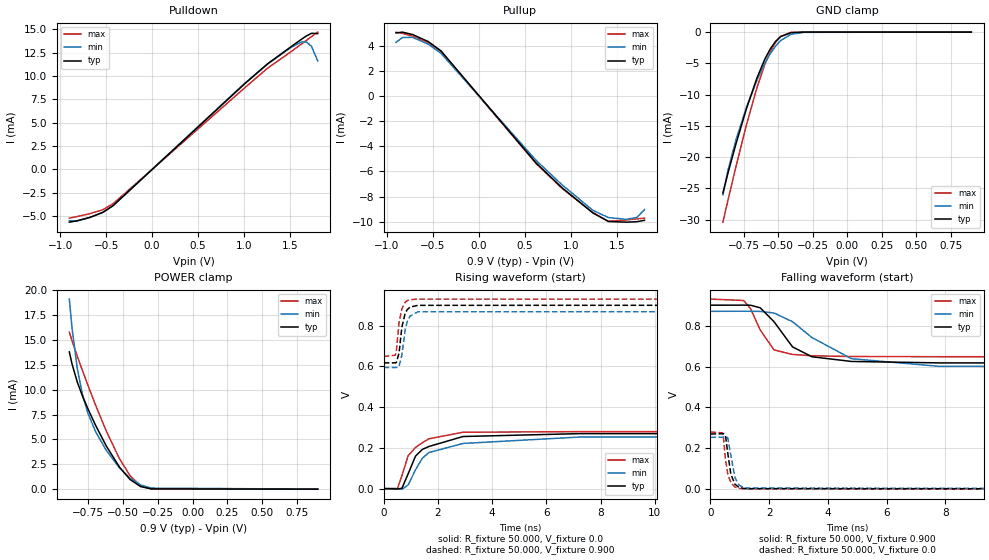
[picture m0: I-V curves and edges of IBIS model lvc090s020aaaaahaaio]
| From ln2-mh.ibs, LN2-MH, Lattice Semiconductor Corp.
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|   Model lvc090s020aaaaahaaio
[Model] lvc090s020aaaaahaaio
| Clamp models do not include dynamic input termination. Please refer to
| the lvc090axxxaaaaahaain model for input termination.
Model_type I/O
Polarity   Non-Inverting
Enable   Active-Low
Vinl =  0.300V
Vinh =  0.600V
Vmeas =  0.500V
Cref =  0.0F
Rref =  1.000M
Vref =  0.0V
C_comp   2.000pF   1.500pF   2.500pF
[Temperature Range]   25.000   0.125k   -40.000
[Voltage Range]   0.900V   0.870V   0.930V
[C Comp Corner]
C_comp   2.000pF   1.500pF   2.500pF
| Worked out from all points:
|   slope of the pulldown table from 0 to 0.135 V, typ, clamps not added: 108 ohm
|   slope of the pullup table from 0 to 0.135 V, typ, clamps not added: 111 ohm
|   GND clamp passes 1 mA (typ) near -0.50 V on its own axis
|   POWER clamp passes 1 mA (typ) near -0.45 V on its own axis
|   rising waveform, R_fixture 50.000, V_fixture 0.0: 20-80 % time 995ps typ, 1.27ns min, 754ps max; typ from 0 V to 0.27 V
|   rising waveform, R_fixture 50.000, V_fixture 0.900: 20-80 % time 174ps typ, 193ps min, 162ps max; typ from 0.617 V to 0.9 V
|   falling waveform, R_fixture 50.000, V_fixture 0.900: 20-80 % time 966ps typ, 1.69ns min, 569ps max; typ from 0.9 V to 0.617 V
|   falling waveform, R_fixture 50.000, V_fixture 0.0: 20-80 % time 173ps typ, 187ps min, 162ps max; typ from 0.27 V to 0 V
[Pulldown]
|Voltage   I(typ)   I(min)   I(max)
-900mV    -5.663mA   -5.504mA   -5.226mA
-816mV    -5.515mA   -5.528mA   -5.062mA
-676mV    -5.144mA   -5.168mA   -4.746mA
-536mV    -4.619mA   -4.596mA   -4.33mA
-424mV    -3.885mA   -3.889mA   -3.679mA
1.004V    9.15mA     9.206mA    8.717mA
1.256V    11.32mA    11.29mA    10.85mA
1.508V    13.13mA    13.06mA    12.6mA
1.62V     13.92mA    13.64mA    13.41mA
1.676V    14.29mA    13.66mA    13.82mA
1.732V    14.58mA    13.18mA    14.23mA
1.8V      14.55mA    11.62mA    14.71mA
[Pullup]
|Voltage   I(typ)   I(min)   I(max)
-900mV    5mA        4.253mA    5.055mA
-832mV    5.071mA    4.644mA    4.974mA
-720mV    4.872mA    4.652mA    4.739mA
-552mV    4.323mA    4.114mA    4.223mA
-412mV    3.575mA    3.382mA    3.541mA
624mV     -5.348mA   -5.137mA   -5.387mA
904mV     -7.299mA   -7.067mA   -7.349mA
1.24V     -9.304mA   -9.096mA   -9.27mA
1.408V    -9.974mA   -9.662mA   -9.959mA
1.604V    -10.03mA   -9.804mA   -9.853mA
1.716V    -9.99mA    -9.653mA   -9.766mA
1.8V      -9.88mA    -9.036mA   -9.711mA
[GND_clamp]
|Voltage   I(typ)   I(min)   I(max)
-900mV    -25.74mA   -26.04mA   -30.41mA
-862mV    -22.43mA   -21.97mA   -26.77mA
-805mV    -17.85mA   -17.2mA    -21.48mA
-729mV    -12.23mA   -12.01mA   -14.81mA
-653mV    -7.318mA   -7.665mA   -8.863mA
-596mV    -4.322mA   -4.979mA   -5.166mA
-558mV    -2.736mA   -3.498mA   -3.192mA
-520mV    -1.528mA   -2.289mA   -1.69mA
-482mV    -716.8uA   -1.366mA   -707.5uA
-406mV    -84.93uA   -343.7uA   -48.42uA
-311mV    -3.638uA   -36.43uA   -951.8nA
900mV     -18.6pA    0A         -11.9pA
[POWER_clamp]
|Voltage   I(typ)   I(min)   I(max)
-886mV    13.81mA    19.12mA    15.79mA
-867mV    12.61mA    16.27mA    14.94mA
-829mV    10.78mA    12.15mA    13.38mA
-791mV    9.351mA    9.485mA    11.9mA
-753mV    8.099mA    7.665mA    10.48mA
-696mV    6.388mA    5.752mA    8.409mA
-620mV    4.338mA    3.895mA    5.839mA
-525mV    2.205mA    2.133mA    3.051mA
-449mV    967uA      1.099mA    1.349mA
-373mV    256.9uA    426.8uA    331.7uA
-297mV    30.15uA    106.2uA    25.19uA
900mV     0A         0A         0A
[Ramp]
| variable   typ   min   max
dV/dt_r   0.162/0.994n   0.152/1.263n   0.168/0.754n
dV/dt_f   0.170/0.980n   0.166/1.702n   0.169/0.571n
R_load = 50.000
[Rising Waveform]
R_fixture= 50.000
V_fixture= 0.0
V_fixture_min= 0.0
V_fixture_max= 0.0
|time   V(typ)   V(min)   V(max)
0s        1.599uV    8.537uV    733nV
507ps     -1.972mV   -233.6uV   204.9uV
673ps     1.525mV    -2.891mV   63.41mV
901ps     72.07mV    17.56mV    160.9mV
1.173ns   159.3mV    91.85mV    201.7mV
1.424ns   192mV      148.8mV    224.7mV
1.671ns   206.7mV    177mV      244.5mV
2.926ns   255.5mV    221.4mV    276.4mV
7.251ns   269.7mV    253.1mV    279.5mV
50ns      269.8mV    253.9mV    279.5mV
[Rising Waveform]
R_fixture= 50.000
V_fixture= 0.900
V_fixture_min= 0.870
V_fixture_max= 0.930
|time   V(typ)   V(min)   V(max)
0s        616.9mV    594.2mV    648mV
435ps     617mV      594.4mV    654.8mV
467ps     618.9mV    594.2mV    674.3mV
567ps     665.3mV    598.9mV    816mV
669ps     791.2mV    653.1mV    882mV
790ps     859mV      777.2mV    913.8mV
868ps     878mV      819.2mV    922.4mV
970ps     890.3mV    846.5mV    927.2mV
1.26ns    899.2mV    867.5mV    929.7mV
50ns      900mV      870mV      930mV
[Falling Waveform]
R_fixture= 50.000
V_fixture= 0.900
V_fixture_min= 0.870
V_fixture_max= 0.930
|time   V(typ)   V(min)   V(max)
0s        900mV      870mV      930mV
1.132ns   900.4mV    870.5mV    923mV
1.372ns   899.6mV    870.3mV    881.3mV
1.693ns   887.3mV    869.6mV    778.9mV
2.165ns   819.2mV    861.8mV    681.1mV
2.795ns   696.1mV    819.4mV    659.1mV
3.454ns   647.8mV    742mV      652.6mV
4.803ns   624.8mV    638.3mV    648.9mV
7.794ns   617.7mV    600.8mV    648mV
50ns      616.9mV    594.2mV    648mV
[Falling Waveform]
R_fixture= 50.000
V_fixture= 0.0
V_fixture_min= 0.0
V_fixture_max= 0.0
|time   V(typ)   V(min)   V(max)
0s        269.8mV    253.9mV    279.5mV
410ps     271.1mV    254.1mV    275.7mV
447ps     271.3mV    254.7mV    243.4mV
512ps     261.2mV    255.9mV    145.3mV
588ps     177.1mV    251.6mV    75.14mV
694ps     73.24mV    166.5mV    31.28mV
833ps     24.34mV    56.93mV    10.58mV
964ps     9.201mV    21.13mV    4.204mV
1.164ns   2.502mV    5.264mV    1.319mV
50ns      1.598uV    8.551uV    732.2nV
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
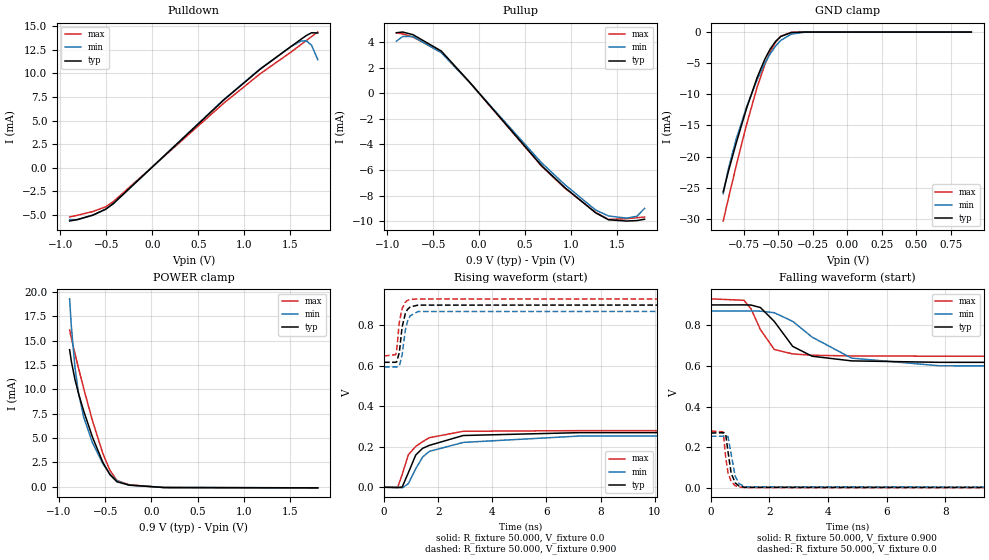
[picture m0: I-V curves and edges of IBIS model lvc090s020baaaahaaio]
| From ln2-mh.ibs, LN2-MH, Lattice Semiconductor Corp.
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|   Model lvc090s020baaaahaaio
[Model] lvc090s020baaaahaaio
| Clamp models do not include dynamic input termination. Please refer to
| the lvc090axxxbaaaahaain model for input termination.
Model_type I/O
Polarity   Non-Inverting
Enable   Active-Low
Vinl =  0.300V
Vinh =  0.600V
Vmeas =  0.500V
Cref =  0.0F
Rref =  1.000M
Vref =  0.0V
C_comp   2.000pF   1.500pF   2.500pF
[Temperature Range]   25.000   0.125k   -40.000
[Voltage Range]   0.900V   0.870V   0.930V
[C Comp Corner]
C_comp   2.000pF   1.500pF   2.500pF
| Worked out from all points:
|   slope of the pulldown table from 0 to 0.135 V, typ, clamps not added: 108 ohm
|   slope of the pullup table from 0 to 0.135 V, typ, clamps not added: 117 ohm
|   GND clamp passes 1 mA (typ) near -0.50 V on its own axis
|   POWER clamp passes 1 mA (typ) near -0.43 V on its own axis
|   rising waveform, R_fixture 50.000, V_fixture 0.0: 20-80 % time 995ps typ, 1.27ns min, 754ps max; typ from 0 V to 0.27 V
|   rising waveform, R_fixture 50.000, V_fixture 0.900: 20-80 % time 174ps typ, 193ps min, 162ps max; typ from 0.617 V to 0.9 V
|   falling waveform, R_fixture 50.000, V_fixture 0.900: 20-80 % time 966ps typ, 1.69ns min, 569ps max; typ from 0.9 V to 0.617 V
|   falling waveform, R_fixture 50.000, V_fixture 0.0: 20-80 % time 173ps typ, 187ps min, 162ps max; typ from 0.27 V to 0 V
[Pulldown]
|Voltage   I(typ)   I(min)   I(max)
-900mV    -5.638mA   -5.478mA   -5.202mA
-816mV    -5.487mA   -5.498mA   -5.034mA
-648mV    -5.015mA   -5.03mA    -4.637mA
-508mV    -4.396mA   -4.378mA   -4.132mA
-424mV    -3.787mA   -3.801mA   -3.579mA
780mV     7.203mA    7.25mA     6.868mA
1.172V    10.43mA    10.47mA    9.948mA
1.508V    12.84mA    12.84mA    12.25mA
1.62V     13.63mA    13.43mA    13.07mA
1.676V    14.01mA    13.45mA    13.48mA
1.732V    14.3mA     12.99mA    13.9mA
1.8V      14.28mA    11.46mA    14.38mA
[Pullup]
|Voltage   I(typ)   I(min)   I(max)
-900mV    4.734mA    4.075mA    4.733mA
-832mV    4.79mA     4.442mA    4.643mA
-720mV    4.584mA    4.435mA    4.4mA
-412mV    3.306mA    3.179mA    3.213mA
-104mV    874.4uA    851.3uA    856.1uA
680mV     -5.664mA   -5.443mA   -5.709mA
932mV     -7.374mA   -7.146mA   -7.42mA
1.268V    -9.357mA   -9.138mA   -9.313mA
1.408V    -9.898mA   -9.601mA   -9.871mA
1.604V    -9.995mA   -9.769mA   -9.815mA
1.716V    -9.961mA   -9.625mA   -9.737mA
1.8V      -9.855mA   -9.012mA   -9.686mA
[GND_clamp]
|Voltage   I(typ)   I(min)   I(max)
-900mV    -25.66mA   -25.96mA   -30.33mA
-862mV    -22.35mA   -21.9mA    -26.69mA
-805mV    -17.77mA   -17.12mA   -21.41mA
-729mV    -12.16mA   -11.94mA   -14.74mA
-653mV    -7.257mA   -7.604mA   -8.799mA
-596mV    -4.271mA   -4.926mA   -5.112mA
-558mV    -2.694mA   -3.452mA   -3.147mA
-520mV    -1.497mA   -2.251mA   -1.658mA
-482mV    -698.8uA   -1.337mA   -690.4uA
-406mV    -81.99uA   -333.1uA   -46.84uA
-311mV    -3.383uA   -34.47uA   -862nA
900mV     0A         0A         0A
[POWER_clamp]
|Voltage   I(typ)   I(min)   I(max)
-886mV    14.08mA    19.3mA     16.11mA
-867mV    12.88mA    16.46mA    15.27mA
-829mV    11.06mA    12.36mA    13.71mA
-791mV    9.635mA    9.695mA    12.24mA
-734mV    7.799mA    7.164mA    10.11mA
-639mV    5.115mA    4.532mA    6.802mA
-525mV    2.491mA    2.349mA    3.394mA
-449mV    1.244mA    1.308mA    1.684mA
-373mV    512.9uA    621.3uA    645.6uA
-240mV    175.8uA    166.1uA    212uA
140mV     -71.31uA   -61.44uA   -81.07uA
1.8V      -102.7uA   -103uA     -104uA
[Ramp]
| variable   typ   min   max
dV/dt_r   0.162/0.994n   0.152/1.263n   0.168/0.754n
dV/dt_f   0.170/0.980n   0.166/1.702n   0.169/0.571n
R_load = 50.000
[Rising Waveform]
R_fixture= 50.000
V_fixture= 0.0
V_fixture_min= 0.0
V_fixture_max= 0.0
|time   V(typ)   V(min)   V(max)
0s        1.599uV    8.537uV    733nV
507ps     -1.972mV   -233.6uV   204.9uV
673ps     1.525mV    -2.891mV   63.41mV
901ps     72.07mV    17.56mV    160.9mV
1.173ns   159.3mV    91.85mV    201.7mV
1.424ns   192mV      148.8mV    224.7mV
1.671ns   206.7mV    177mV      244.5mV
2.926ns   255.5mV    221.4mV    276.4mV
7.251ns   269.7mV    253.1mV    279.5mV
50ns      269.8mV    253.9mV    279.5mV
[Rising Waveform]
R_fixture= 50.000
V_fixture= 0.900
V_fixture_min= 0.870
V_fixture_max= 0.930
|time   V(typ)   V(min)   V(max)
0s        616.9mV    594.2mV    648mV
435ps     617mV      594.4mV    654.8mV
467ps     618.9mV    594.2mV    674.3mV
567ps     665.3mV    598.9mV    816mV
669ps     791.2mV    653.1mV    882mV
790ps     859mV      777.2mV    913.8mV
868ps     878mV      819.2mV    922.4mV
970ps     890.3mV    846.5mV    927.2mV
1.26ns    899.2mV    867.5mV    929.7mV
50ns      900mV      870mV      930mV
[Falling Waveform]
R_fixture= 50.000
V_fixture= 0.900
V_fixture_min= 0.870
V_fixture_max= 0.930
|time   V(typ)   V(min)   V(max)
0s        900mV      870mV      930mV
1.132ns   900.4mV    870.5mV    923mV
1.372ns   899.6mV    870.3mV    881.3mV
1.693ns   887.3mV    869.6mV    778.9mV
2.165ns   819.2mV    861.8mV    681.1mV
2.795ns   696.1mV    819.4mV    659.1mV
3.454ns   647.8mV    742mV      652.6mV
4.803ns   624.8mV    638.3mV    648.9mV
7.794ns   617.7mV    600.8mV    648mV
50ns      616.9mV    594.2mV    648mV
[Falling Waveform]
R_fixture= 50.000
V_fixture= 0.0
V_fixture_min= 0.0
V_fixture_max= 0.0
|time   V(typ)   V(min)   V(max)
0s        269.8mV    253.9mV    279.5mV
410ps     271.1mV    254.1mV    275.7mV
447ps     271.3mV    254.7mV    243.4mV
512ps     261.2mV    255.9mV    145.3mV
588ps     177.1mV    251.6mV    75.14mV
694ps     73.24mV    166.5mV    31.28mV
833ps     24.34mV    56.93mV    10.58mV
964ps     9.201mV    21.13mV    4.204mV
1.164ns   2.502mV    5.264mV    1.319mV
50ns      1.598uV    8.551uV    732.2nV
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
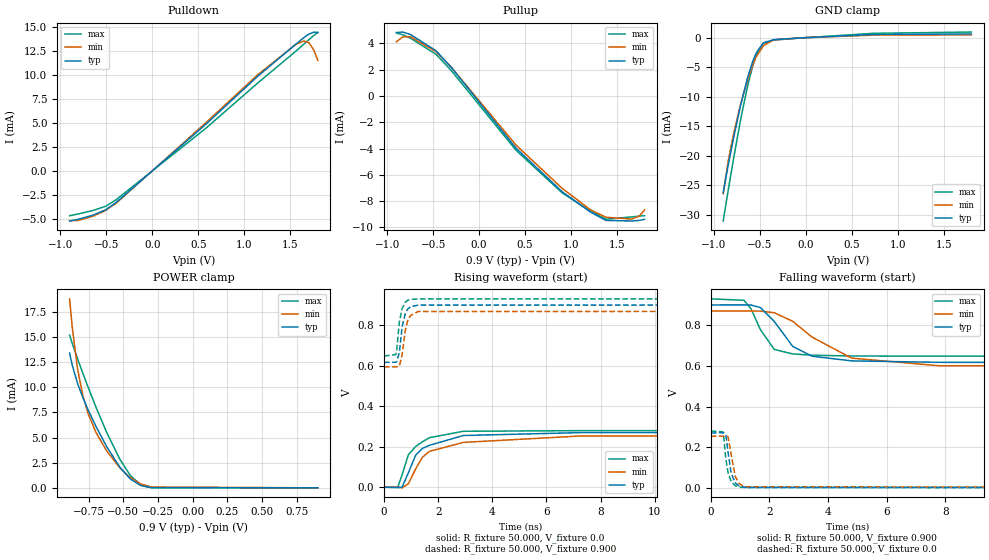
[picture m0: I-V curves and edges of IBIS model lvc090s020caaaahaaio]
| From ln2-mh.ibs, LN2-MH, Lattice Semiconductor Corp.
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|   Model lvc090s020caaaahaaio
[Model] lvc090s020caaaahaaio
| Clamp models do not include dynamic input termination. Please refer to
| the lvc090axxxcaaaahaain model for input termination.
Model_type I/O
Polarity   Non-Inverting
Enable   Active-Low
Vinl =  0.300V
Vinh =  0.600V
Vmeas =  0.500V
Cref =  0.0F
Rref =  1.000M
Vref =  0.0V
C_comp   2.000pF   1.500pF   2.500pF
[Temperature Range]   25.000   0.125k   -40.000
[Voltage Range]   0.900V   0.870V   0.930V
[C Comp Corner]
C_comp   2.000pF   1.500pF   2.500pF
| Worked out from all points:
|   slope of the pulldown table from 0 to 0.135 V, typ, clamps not added: 121 ohm
|   slope of the pullup table from 0 to 0.135 V, typ, clamps not added: 112 ohm
|   GND clamp passes 1 mA (typ) near -0.47 V on its own axis
|   POWER clamp passes 1 mA (typ) near -0.46 V on its own axis
|   rising waveform, R_fixture 50.000, V_fixture 0.0: 20-80 % time 995ps typ, 1.27ns min, 754ps max; typ from 0 V to 0.27 V
|   rising waveform, R_fixture 50.000, V_fixture 0.900: 20-80 % time 174ps typ, 193ps min, 162ps max; typ from 0.617 V to 0.9 V
|   falling waveform, R_fixture 50.000, V_fixture 0.900: 20-80 % time 966ps typ, 1.69ns min, 569ps max; typ from 0.9 V to 0.617 V
|   falling waveform, R_fixture 50.000, V_fixture 0.0: 20-80 % time 173ps typ, 187ps min, 162ps max; typ from 0.27 V to 0 V
[Pulldown]
|Voltage   I(typ)   I(min)   I(max)
-900mV    -5.173mA   -5.125mA   -4.627mA
-816mV    -5.022mA   -5.134mA   -4.463mA
-648mV    -4.572mA   -4.681mA   -4.086mA
-508mV    -4.013mA   -4.077mA   -3.645mA
-396mV    -3.26mA    -3.347mA   -2.976mA
584mV     4.889mA    5.046mA    4.469mA
1.144V    9.832mA    9.989mA    9.132mA
1.564V    13.21mA    13.19mA    12.48mA
1.648V    13.86mA    13.52mA    13.18mA
1.704V    14.24mA    13.35mA    13.66mA
1.76V     14.45mA    12.53mA    14.12mA
1.8V      14.38mA    11.51mA    14.43mA
[Pullup]
|Voltage   I(typ)   I(min)   I(max)
-900mV    4.829mA    4.131mA    4.795mA
-832mV    4.869mA    4.495mA    4.662mA
-748mV    4.687mA    4.517mA    4.406mA
-468mV    3.441mA    3.369mA    3.168mA
-300mV    2.152mA    2.164mA    1.911mA
400mV     -3.965mA   -3.728mA   -4.12mA
904mV     -7.295mA   -7.04mA    -7.38mA
1.212V    -8.842mA   -8.667mA   -8.785mA
1.38V     -9.474mA   -9.235mA   -9.382mA
1.66V     -9.521mA   -9.375mA   -9.209mA
1.744V    -9.477mA   -9.143mA   -9.15mA
1.8V      -9.39mA    -8.671mA   -9.112mA
[GND_clamp]
|Voltage   I(typ)   I(min)   I(max)
-900mV    -26.23mA   -26.42mA   -31.01mA
-843mV    -21.35mA   -20.64mA   -25.59mA
-786mV    -16.88mA   -16.2mA    -20.37mA
-710mV    -11.41mA   -11.24mA   -13.83mA
-634mV    -6.729mA   -7.102mA   -8.134mA
-577mV    -3.961mA   -4.589mA   -4.707mA
-539mV    -2.551mA   -3.235mA   -2.953mA
-463mV    -890.5uA   -1.367mA   -946.5uA
-349mV    -352.6uA   -378.2uA   -421.6uA
-45mV     -42.8uA    -36.37uA   -52.77uA
734mV     527.5uA    410.9uA    719.1uA
1.8V      610uA      464.4uA    937.2uA
[POWER_clamp]
|Voltage   I(typ)   I(min)   I(max)
-886mV    13.4mA     18.79mA    15.19mA
-867mV    12.2mA     15.95mA    14.36mA
-829mV    10.39mA    11.85mA    12.84mA
-791mV    8.986mA    9.193mA    11.4mA
-753mV    7.76mA     7.389mA    10.02mA
-696mV    6.096mA    5.502mA    8.018mA
-620mV    4.114mA    3.69mA     5.536mA
-525mV    2.063mA    1.993mA    2.854mA
-449mV    884.5uA    1.009mA    1.231mA
-373mV    221.5uA    379.3uA    279.5uA
-297mV    19.57uA    87.58uA    7.748uA
900mV     0A         0A         0A
[Ramp]
| variable   typ   min   max
dV/dt_r   0.162/0.994n   0.152/1.263n   0.168/0.754n
dV/dt_f   0.170/0.980n   0.166/1.702n   0.169/0.571n
R_load = 50.000
[Rising Waveform]
R_fixture= 50.000
V_fixture= 0.0
V_fixture_min= 0.0
V_fixture_max= 0.0
|time   V(typ)   V(min)   V(max)
0s        1.599uV    8.537uV    733nV
507ps     -1.972mV   -233.6uV   204.9uV
673ps     1.525mV    -2.891mV   63.41mV
901ps     72.07mV    17.56mV    160.9mV
1.173ns   159.3mV    91.85mV    201.7mV
1.424ns   192mV      148.8mV    224.7mV
1.671ns   206.7mV    177mV      244.5mV
2.926ns   255.5mV    221.4mV    276.4mV
7.251ns   269.7mV    253.1mV    279.5mV
50ns      269.8mV    253.9mV    279.5mV
[Rising Waveform]
R_fixture= 50.000
V_fixture= 0.900
V_fixture_min= 0.870
V_fixture_max= 0.930
|time   V(typ)   V(min)   V(max)
0s        616.9mV    594.2mV    648mV
435ps     617mV      594.4mV    654.8mV
467ps     618.9mV    594.2mV    674.3mV
567ps     665.3mV    598.9mV    816mV
669ps     791.2mV    653.1mV    882mV
790ps     859mV      777.2mV    913.8mV
868ps     878mV      819.2mV    922.4mV
970ps     890.3mV    846.5mV    927.2mV
1.26ns    899.2mV    867.5mV    929.7mV
50ns      900mV      870mV      930mV
[Falling Waveform]
R_fixture= 50.000
V_fixture= 0.900
V_fixture_min= 0.870
V_fixture_max= 0.930
|time   V(typ)   V(min)   V(max)
0s        900mV      870mV      930mV
1.132ns   900.4mV    870.5mV    923mV
1.372ns   899.6mV    870.3mV    881.3mV
1.693ns   887.3mV    869.6mV    778.9mV
2.165ns   819.2mV    861.8mV    681.1mV
2.795ns   696.1mV    819.4mV    659.1mV
3.454ns   647.8mV    742mV      652.6mV
4.803ns   624.8mV    638.3mV    648.9mV
7.794ns   617.7mV    600.8mV    648mV
50ns      616.9mV    594.2mV    648mV
[Falling Waveform]
R_fixture= 50.000
V_fixture= 0.0
V_fixture_min= 0.0
V_fixture_max= 0.0
|time   V(typ)   V(min)   V(max)
0s        269.8mV    253.9mV    279.5mV
410ps     271.1mV    254.1mV    275.7mV
447ps     271.3mV    254.7mV    243.4mV
512ps     261.2mV    255.9mV    145.3mV
588ps     177.1mV    251.6mV    75.14mV
694ps     73.24mV    166.5mV    31.28mV
833ps     24.34mV    56.93mV    10.58mV
964ps     9.201mV    21.13mV    4.204mV
1.164ns   2.502mV    5.264mV    1.319mV
50ns      1.598uV    8.551uV    732.2nV
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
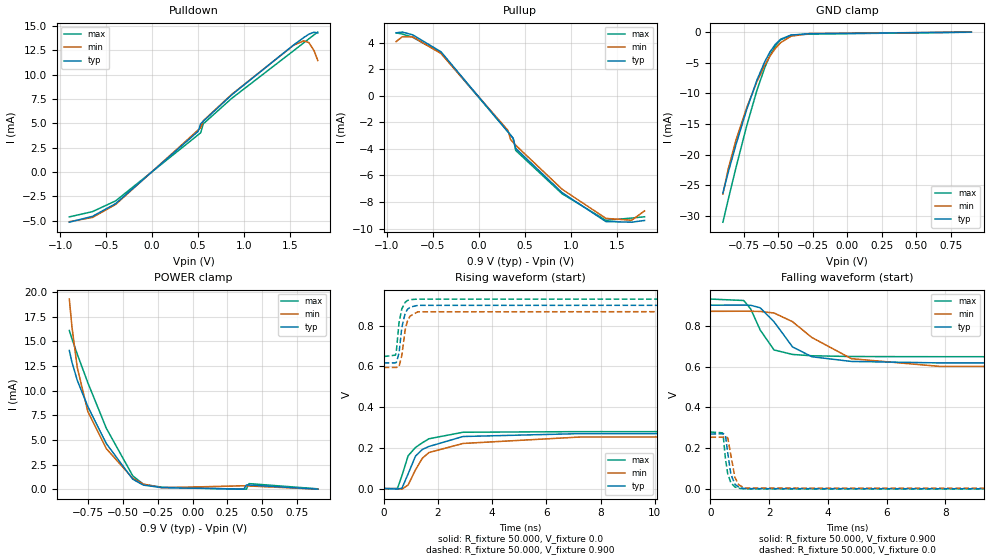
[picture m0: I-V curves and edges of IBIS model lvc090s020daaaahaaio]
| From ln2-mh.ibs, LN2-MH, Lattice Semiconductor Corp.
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|   Model lvc090s020daaaahaaio
[Model] lvc090s020daaaahaaio
| Clamp models do not include dynamic input termination. Please refer to
| the lvc090axxxdaaaahaain model for input termination.
Model_type I/O
Polarity   Non-Inverting
Enable   Active-Low
Vinl =  0.300V
Vinh =  0.600V
Vmeas =  0.500V
Cref =  0.0F
Rref =  1.000M
Vref =  0.0V
C_comp   2.000pF   1.500pF   2.500pF
[Temperature Range]   25.000   0.125k   -40.000
[Voltage Range]   0.900V   0.870V   0.930V
[C Comp Corner]
C_comp   2.000pF   1.500pF   2.500pF
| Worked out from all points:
|   slope of the pulldown table from 0 to 0.135 V, typ, clamps not added: 121 ohm
|   slope of the pullup table from 0 to 0.135 V, typ, clamps not added: 117 ohm
|   GND clamp passes 1 mA (typ) near -0.47 V on its own axis
|   POWER clamp passes 1 mA (typ) near -0.43 V on its own axis
|   rising waveform, R_fixture 50.000, V_fixture 0.0: 20-80 % time 995ps typ, 1.27ns min, 754ps max; typ from 0 V to 0.27 V
|   rising waveform, R_fixture 50.000, V_fixture 0.900: 20-80 % time 174ps typ, 193ps min, 162ps max; typ from 0.617 V to 0.9 V
|   falling waveform, R_fixture 50.000, V_fixture 0.900: 20-80 % time 966ps typ, 1.69ns min, 569ps max; typ from 0.9 V to 0.617 V
|   falling waveform, R_fixture 50.000, V_fixture 0.0: 20-80 % time 173ps typ, 187ps min, 162ps max; typ from 0.27 V to 0 V
[Pulldown]
|Voltage   I(typ)   I(min)   I(max)
-900mV    -5.173mA   -5.125mA   -4.627mA
-648mV    -4.572mA   -4.681mA   -4.086mA
-396mV    -3.26mA    -3.347mA   -2.976mA
500mV     4.172mA    4.309mA    3.814mA
528mV     4.952mA    4.554mA    4.031mA
556mV     5.206mA    5.262mA    4.944mA
864mV     7.918mA    7.966mA    7.555mA
1.536V    13.04mA    13.02mA    12.45mA
1.648V    13.82mA    13.48mA    13.28mA
1.704V    14.17mA    13.3mA     13.69mA
1.76V     14.37mA    12.47mA    14.1mA
1.8V      14.28mA    11.46mA    14.38mA
[Pullup]
|Voltage   I(typ)   I(min)   I(max)
-900mV    4.734mA    4.075mA    4.733mA
-832mV    4.79mA     4.442mA    4.643mA
-720mV    4.584mA    4.435mA    4.4mA
-412mV    3.306mA    3.179mA    3.213mA
316mV     -2.722mA   -2.615mA   -2.722mA
344mV     -2.963mA   -3.297mA   -2.965mA
372mV     -3.203mA   -3.514mA   -3.208mA
400mV     -3.965mA   -3.728mA   -4.12mA
904mV     -7.295mA   -7.04mA    -7.38mA
1.38V     -9.474mA   -9.235mA   -9.382mA
1.66V     -9.521mA   -9.375mA   -9.209mA
1.8V      -9.39mA    -8.671mA   -9.112mA
[GND_clamp]
|Voltage   I(typ)   I(min)   I(max)
-900mV    -26.23mA   -26.42mA   -31.01mA
-862mV    -22.92mA   -22.36mA   -27.37mA
-805mV    -18.34mA   -17.59mA   -22.08mA
-729mV    -12.72mA   -12.41mA   -15.41mA
-653mV    -7.804mA   -8.056mA   -9.454mA
-596mV    -4.802mA   -5.365mA   -5.752mA
-558mV    -3.209mA   -3.878mA   -3.771mA
-520mV    -1.991mA   -2.661mA   -2.259mA
-482mV    -1.164mA   -1.727mA   -1.259mA
-406mV    -478.8uA   -668.8uA   -533.3uA
-273mV    -266uA     -238.6uA   -325.5uA
900mV     -290.6nA   1.13uA     -22.03uA
[POWER_clamp]
|Voltage   I(typ)   I(min)   I(max)
-886mV    14.08mA    19.3mA     16.11mA
-867mV    12.88mA    16.46mA    15.27mA
-829mV    11.06mA    12.36mA    13.71mA
-753mV    8.386mA    7.879mA    10.81mA
-620mV    4.627mA    4.114mA    6.183mA
-430mV    1.011mA    1.102mA    1.355mA
-354mV    411uA      505.3uA    502.8uA
-221mV    159.2uA    144.5uA    192.7uA
368mV     0A         343.5uA    0A
387mV     431.3uA    334.2uA    0A
406mV     418.8uA    324.3uA    563.7uA
900mV     0A         0A         34.92uA
[Ramp]
| variable   typ   min   max
dV/dt_r   0.162/0.994n   0.152/1.263n   0.168/0.754n
dV/dt_f   0.170/0.980n   0.166/1.702n   0.169/0.571n
R_load = 50.000
[Rising Waveform]
R_fixture= 50.000
V_fixture= 0.0
V_fixture_min= 0.0
V_fixture_max= 0.0
|time   V(typ)   V(min)   V(max)
0s        1.599uV    8.537uV    733nV
507ps     -1.972mV   -233.6uV   204.9uV
673ps     1.525mV    -2.891mV   63.41mV
901ps     72.07mV    17.56mV    160.9mV
1.173ns   159.3mV    91.85mV    201.7mV
1.424ns   192mV      148.8mV    224.7mV
1.671ns   206.7mV    177mV      244.5mV
2.926ns   255.5mV    221.4mV    276.4mV
7.251ns   269.7mV    253.1mV    279.5mV
50ns      269.8mV    253.9mV    279.5mV
[Rising Waveform]
R_fixture= 50.000
V_fixture= 0.900
V_fixture_min= 0.870
V_fixture_max= 0.930
|time   V(typ)   V(min)   V(max)
0s        616.9mV    594.2mV    648mV
435ps     617mV      594.4mV    654.8mV
467ps     618.9mV    594.2mV    674.3mV
567ps     665.3mV    598.9mV    816mV
669ps     791.2mV    653.1mV    882mV
790ps     859mV      777.2mV    913.8mV
868ps     878mV      819.2mV    922.4mV
970ps     890.3mV    846.5mV    927.2mV
1.26ns    899.2mV    867.5mV    929.7mV
50ns      900mV      870mV      930mV
[Falling Waveform]
R_fixture= 50.000
V_fixture= 0.900
V_fixture_min= 0.870
V_fixture_max= 0.930
|time   V(typ)   V(min)   V(max)
0s        900mV      870mV      930mV
1.132ns   900.4mV    870.5mV    923mV
1.372ns   899.6mV    870.3mV    881.3mV
1.693ns   887.3mV    869.6mV    778.9mV
2.165ns   819.2mV    861.8mV    681.1mV
2.795ns   696.1mV    819.4mV    659.1mV
3.454ns   647.8mV    742mV      652.6mV
4.803ns   624.8mV    638.3mV    648.9mV
7.794ns   617.7mV    600.8mV    648mV
50ns      616.9mV    594.2mV    648mV
[Falling Waveform]
R_fixture= 50.000
V_fixture= 0.0
V_fixture_min= 0.0
V_fixture_max= 0.0
|time   V(typ)   V(min)   V(max)
0s        269.8mV    253.9mV    279.5mV
410ps     271.1mV    254.1mV    275.7mV
447ps     271.3mV    254.7mV    243.4mV
512ps     261.2mV    255.9mV    145.3mV
588ps     177.1mV    251.6mV    75.14mV
694ps     73.24mV    166.5mV    31.28mV
833ps     24.34mV    56.93mV    10.58mV
964ps     9.201mV    21.13mV    4.204mV
1.164ns   2.502mV    5.264mV    1.319mV
50ns      1.598uV    8.551uV    732.2nV
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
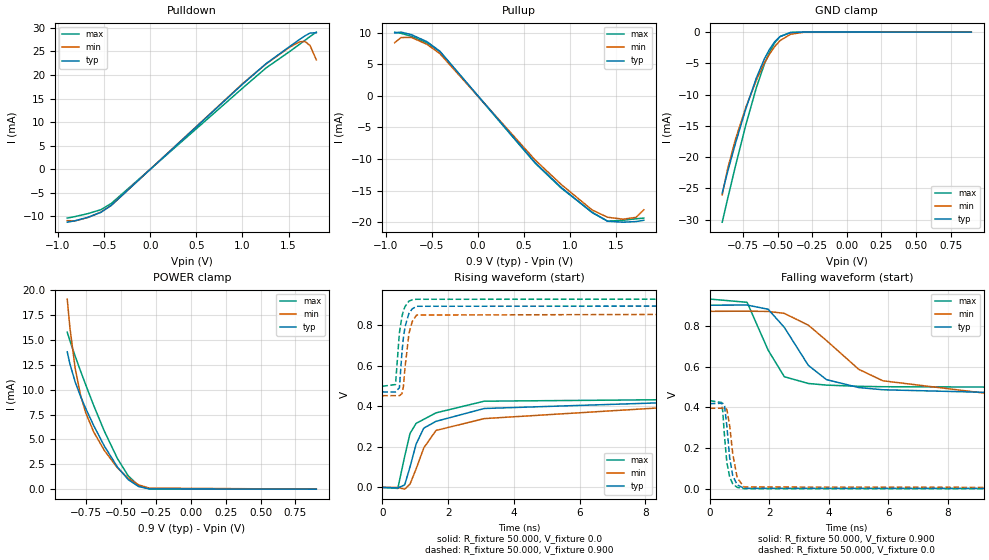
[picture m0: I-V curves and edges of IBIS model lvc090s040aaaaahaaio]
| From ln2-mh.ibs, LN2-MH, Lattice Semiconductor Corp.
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|   Model lvc090s040aaaaahaaio
[Model] lvc090s040aaaaahaaio
| Clamp models do not include dynamic input termination. Please refer to
| the lvc090axxxaaaaahaain model for input termination.
Model_type I/O
Polarity   Non-Inverting
Enable   Active-Low
Vinl =  0.300V
Vinh =  0.600V
Vmeas =  0.500V
Cref =  0.0F
Rref =  1.000M
Vref =  0.0V
C_comp   2.000pF   1.500pF   2.500pF
[Temperature Range]   25.000   0.125k   -40.000
[Voltage Range]   0.900V   0.870V   0.930V
[C Comp Corner]
C_comp   2.000pF   1.500pF   2.500pF
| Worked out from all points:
|   slope of the pulldown table from 0 to 0.135 V, typ, clamps not added: 54.8 ohm
|   slope of the pullup table from 0 to 0.135 V, typ, clamps not added: 55.9 ohm
|   GND clamp passes 1 mA (typ) near -0.50 V on its own axis
|   POWER clamp passes 1 mA (typ) near -0.45 V on its own axis
|   rising waveform, R_fixture 50.000, V_fixture 0.0: 20-80 % time 1.02ns typ, 1.29ns min, 783ps max; typ from 0 V to 0.418 V
|   rising waveform, R_fixture 50.000, V_fixture 0.900: 20-80 % time 166ps typ, 183ps min, 158ps max; typ from 0.471 V to 0.9 V
|   falling waveform, R_fixture 50.000, V_fixture 0.900: 20-80 % time 1.26ns typ, 2.24ns min, 719ps max; typ from 0.9 V to 0.471 V
|   falling waveform, R_fixture 50.000, V_fixture 0.0: 20-80 % time 184ps typ, 210ps min, 168ps max; typ from 0.418 V to 0 V
[Pulldown]
|Voltage   I(typ)   I(min)   I(max)
-900mV    -11.24mA   -10.92mA   -10.37mA
-816mV    -10.94mA   -10.96mA   -10.05mA
-676mV    -10.21mA   -10.25mA   -9.424mA
-536mV    -9.161mA   -9.109mA   -8.595mA
-424mV    -7.689mA   -7.698mA   -7.287mA
1.004V    18.11mA    18.21mA    17.26mA
1.256V    22.41mA    22.35mA    21.5mA
1.508V    25.99mA    25.86mA    24.93mA
1.62V     27.55mA    27.04mA    26.53mA
1.676V    28.29mA    27.12mA    27.34mA
1.732V    28.9mA     26.26mA    28.16mA
1.8V      28.95mA    23.22mA    29.1mA
[Pullup]
|Voltage   I(typ)   I(min)   I(max)
-900mV    9.971mA    8.422mA    10.08mA
-832mV    10.1mA     9.238mA    9.91mA
-720mV    9.7mA      9.259mA    9.435mA
-552mV    8.592mA    8.175mA    8.397mA
-412mV    7.089mA    6.707mA    7.025mA
624mV     -10.6mA    -10.18mA   -10.68mA
904mV     -14.49mA   -14.02mA   -14.59mA
1.24V     -18.48mA   -18.07mA   -18.43mA
1.408V    -19.85mA   -19.22mA   -19.84mA
1.576V    -20mA      -19.52mA   -19.69mA
1.716V    -19.9mA    -19.23mA   -19.46mA
1.8V      -19.7mA    -18.04mA   -19.35mA
[GND_clamp]
|Voltage   I(typ)   I(min)   I(max)
-900mV    -25.74mA   -26.04mA   -30.41mA
-862mV    -22.43mA   -21.97mA   -26.77mA
-805mV    -17.85mA   -17.2mA    -21.48mA
-729mV    -12.23mA   -12.01mA   -14.81mA
-653mV    -7.318mA   -7.665mA   -8.863mA
-596mV    -4.322mA   -4.979mA   -5.166mA
-558mV    -2.736mA   -3.498mA   -3.192mA
-520mV    -1.528mA   -2.289mA   -1.69mA
-482mV    -716.8uA   -1.366mA   -707.5uA
-406mV    -84.93uA   -343.7uA   -48.42uA
-311mV    -3.638uA   -36.43uA   -951.8nA
900mV     -18.66pA   0A         -11.84pA
[POWER_clamp]
|Voltage   I(typ)   I(min)   I(max)
-886mV    13.81mA    19.12mA    15.79mA
-867mV    12.61mA    16.27mA    14.94mA
-829mV    10.78mA    12.15mA    13.38mA
-791mV    9.351mA    9.485mA    11.9mA
-753mV    8.099mA    7.665mA    10.48mA
-696mV    6.388mA    5.752mA    8.409mA
-620mV    4.338mA    3.895mA    5.839mA
-525mV    2.205mA    2.133mA    3.051mA
-449mV    967uA      1.099mA    1.349mA
-373mV    256.9uA    426.8uA    331.7uA
-297mV    30.15uA    106.2uA    25.19uA
900mV     0A         0A         0A
[Ramp]
| variable   typ   min   max
dV/dt_r   0.251/1.019n   0.237/1.289n   0.260/0.783n
dV/dt_f   0.257/1.279n   0.250/2.251n   0.258/0.724n
R_load = 50.000
[Rising Waveform]
R_fixture= 50.000
V_fixture= 0.0
V_fixture_min= 0.0
V_fixture_max= 0.0
|time   V(typ)   V(min)   V(max)
0s        1.176uV    6.304uV    543.6nV
472ps     -2.56mV    -267.7uV   -5.05mV
681ps     12.29mV    -8.753mV   153.2mV
843ps     100.9mV    15.97mV    266.2mV
1.029ns   214.3mV    91.5mV     316.2mV
1.262ns   292.7mV    195.1mV    336.2mV
1.633ns   326.2mV    281.2mV    368.1mV
3.099ns   389.6mV    339.7mV    425.7mV
8.502ns   418mV      393.5mV    432.9mV
50ns      418.3mV    395.7mV    432.9mV
[Rising Waveform]
R_fixture= 50.000
V_fixture= 0.900
V_fixture_min= 0.870
V_fixture_max= 0.930
|time   V(typ)   V(min)   V(max)
0s        471.4mV    453mV      499.4mV
402ps     471mV      453mV      507.9mV
521ps     492.6mV    452.8mV    763.7mV
600ps     671.1mV    463.3mV    845.9mV
642ps     739.2mV    497.4mV    871.4mV
693ps     794.6mV    594.6mV    893.6mV
812ps     859.7mV    761.1mV    919.8mV
910ps     881.7mV    819mV      926.5mV
1.041ns   894.4mV    851.1mV    929mV
50ns      900mV      870mV      930mV
[Falling Waveform]
R_fixture= 50.000
V_fixture= 0.900
V_fixture_min= 0.870
V_fixture_max= 0.930
|time   V(typ)   V(min)   V(max)
0s        900mV      870mV      930mV
1.253ns   900.7mV    870.7mV    914.1mV
1.96ns    880.2mV    869.5mV    680mV
2.504ns   791.3mV    860mV      550mV
3.311ns   605.4mV    802.2mV    517mV
3.919ns   535.9mV    727.1mV    509.1mV
5.002ns   497.1mV    586.3mV    503.1mV
5.812ns   486.3mV    530.2mV    501.2mV
9.362ns   473.3mV    467.5mV    499.5mV
50ns      471.4mV    453mV      499.4mV
[Falling Waveform]
R_fixture= 50.000
V_fixture= 0.0
V_fixture_min= 0.0
V_fixture_max= 0.0
|time   V(typ)   V(min)   V(max)
0s        418.3mV    395.7mV    432.9mV
396ps     420mV      395.9mV    424mV
437ps     419.8mV    396.8mV    378mV
496ps     406.5mV    398.1mV    257.4mV
574ps     308.2mV    390.3mV    130.2mV
669ps     152.3mV    309.7mV    58.87mV
771ps     66.31mV    173.1mV    26.19mV
921ps     21.04mV    54.86mV    8.718mV
1.15ns    4.482mV    10.69mV    2.474mV
50ns      1.175uV    6.313uV    542.9nV
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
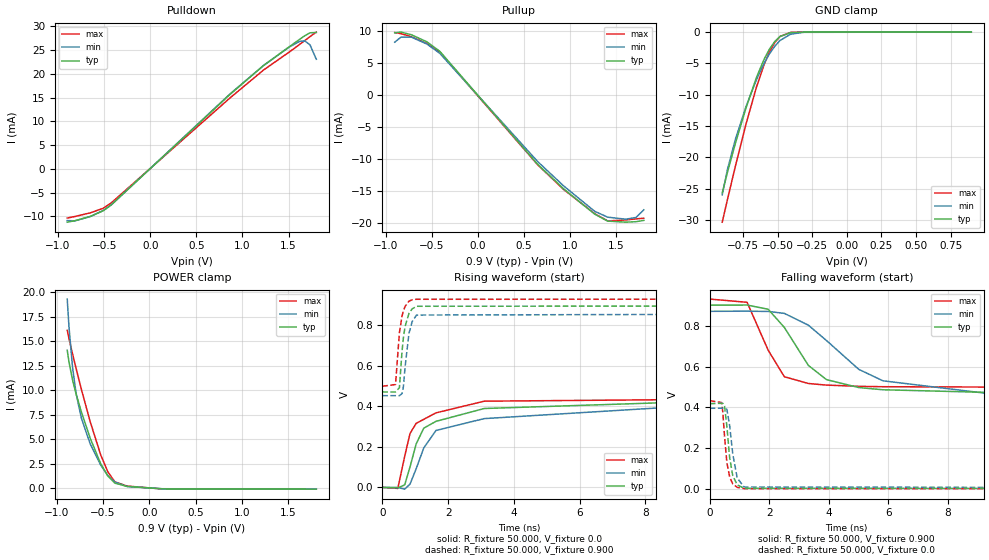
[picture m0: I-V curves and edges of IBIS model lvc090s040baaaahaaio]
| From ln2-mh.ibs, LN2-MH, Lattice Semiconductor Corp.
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|   Model lvc090s040baaaahaaio
[Model] lvc090s040baaaahaaio
| Clamp models do not include dynamic input termination. Please refer to
| the lvc090axxxbaaaahaain model for input termination.
Model_type I/O
Polarity   Non-Inverting
Enable   Active-Low
Vinl =  0.300V
Vinh =  0.600V
Vmeas =  0.500V
Cref =  0.0F
Rref =  1.000M
Vref =  0.0V
C_comp   2.000pF   1.500pF   2.500pF
[Temperature Range]   25.000   0.125k   -40.000
[Voltage Range]   0.900V   0.870V   0.930V
[C Comp Corner]
C_comp   2.000pF   1.500pF   2.500pF
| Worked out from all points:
|   slope of the pulldown table from 0 to 0.135 V, typ, clamps not added: 54.8 ohm
|   slope of the pullup table from 0 to 0.135 V, typ, clamps not added: 57.6 ohm
|   GND clamp passes 1 mA (typ) near -0.50 V on its own axis
|   POWER clamp passes 1 mA (typ) near -0.43 V on its own axis
|   rising waveform, R_fixture 50.000, V_fixture 0.0: 20-80 % time 1.02ns typ, 1.29ns min, 783ps max; typ from 0 V to 0.418 V
|   rising waveform, R_fixture 50.000, V_fixture 0.900: 20-80 % time 166ps typ, 183ps min, 158ps max; typ from 0.471 V to 0.9 V
|   falling waveform, R_fixture 50.000, V_fixture 0.900: 20-80 % time 1.26ns typ, 2.24ns min, 719ps max; typ from 0.9 V to 0.471 V
|   falling waveform, R_fixture 50.000, V_fixture 0.0: 20-80 % time 184ps typ, 210ps min, 168ps max; typ from 0.418 V to 0 V
[Pulldown]
|Voltage   I(typ)   I(min)   I(max)
-900mV    -11.22mA   -10.89mA   -10.35mA
-816mV    -10.91mA   -10.93mA   -10.02mA
-648mV    -9.994mA   -10.02mA   -9.246mA
-508mV    -8.789mA   -8.742mA   -8.275mA
-424mV    -7.591mA   -7.609mA   -7.186mA
864mV     15.65mA    15.75mA    14.91mA
1.228V    21.74mA    21.74mA    20.79mA
1.508V    25.7mA     25.64mA    24.59mA
1.62V     27.26mA    26.82mA    26.19mA
1.676V    28.01mA    26.92mA    27mA
1.732V    28.62mA    26.07mA    27.82mA
1.8V      28.69mA    23.06mA    28.77mA
[Pullup]
|Voltage   I(typ)   I(min)   I(max)
-900mV    9.705mA    8.244mA    9.756mA
-832mV    9.823mA    9.035mA    9.579mA
-720mV    9.411mA    9.041mA    9.096mA
-552mV    8.303mA    7.957mA    8.053mA
-412mV    6.82mA     6.504mA    6.697mA
652mV     -10.92mA   -10.49mA   -11mA
932mV     -14.74mA   -14.28mA   -14.84mA
1.268V    -18.69mA   -18.25mA   -18.62mA
1.408V    -19.78mA   -19.16mA   -19.75mA
1.604V    -19.95mA   -19.48mA   -19.6mA
1.716V    -19.87mA   -19.21mA   -19.43mA
1.8V      -19.67mA   -18.02mA   -19.33mA
[GND_clamp]
|Voltage   I(typ)   I(min)   I(max)
-900mV    -25.66mA   -25.96mA   -30.33mA
-862mV    -22.35mA   -21.9mA    -26.69mA
-805mV    -17.77mA   -17.12mA   -21.41mA
-729mV    -12.16mA   -11.94mA   -14.74mA
-653mV    -7.257mA   -7.604mA   -8.799mA
-596mV    -4.271mA   -4.926mA   -5.112mA
-558mV    -2.694mA   -3.451mA   -3.147mA
-520mV    -1.497mA   -2.251mA   -1.658mA
-482mV    -698.8uA   -1.337mA   -690.4uA
-406mV    -81.99uA   -333.1uA   -46.84uA
-311mV    -3.383uA   -34.47uA   -862nA
900mV     0A         0A         0A
[POWER_clamp]
|Voltage   I(typ)   I(min)   I(max)
-886mV    14.08mA    19.3mA     16.11mA
-867mV    12.88mA    16.46mA    15.27mA
-829mV    11.06mA    12.36mA    13.71mA
-791mV    9.635mA    9.695mA    12.24mA
-734mV    7.799mA    7.164mA    10.11mA
-639mV    5.115mA    4.532mA    6.802mA
-525mV    2.491mA    2.349mA    3.394mA
-449mV    1.244mA    1.308mA    1.684mA
-373mV    512.9uA    621.3uA    645.6uA
-240mV    175.8uA    166.1uA    212uA
140mV     -71.31uA   -61.44uA   -81.07uA
1.8V      -102.7uA   -103uA     -104uA
[Ramp]
| variable   typ   min   max
dV/dt_r   0.251/1.019n   0.237/1.289n   0.260/0.783n
dV/dt_f   0.257/1.279n   0.250/2.251n   0.258/0.724n
R_load = 50.000
[Rising Waveform]
R_fixture= 50.000
V_fixture= 0.0
V_fixture_min= 0.0
V_fixture_max= 0.0
|time   V(typ)   V(min)   V(max)
0s        1.176uV    6.304uV    543.6nV
472ps     -2.56mV    -267.7uV   -5.05mV
681ps     12.29mV    -8.753mV   153.2mV
843ps     100.9mV    15.97mV    266.2mV
1.029ns   214.3mV    91.5mV     316.2mV
1.262ns   292.7mV    195.1mV    336.2mV
1.633ns   326.2mV    281.2mV    368.1mV
3.099ns   389.6mV    339.7mV    425.7mV
8.502ns   418mV      393.5mV    432.9mV
50ns      418.3mV    395.7mV    432.9mV
[Rising Waveform]
R_fixture= 50.000
V_fixture= 0.900
V_fixture_min= 0.870
V_fixture_max= 0.930
|time   V(typ)   V(min)   V(max)
0s        471.4mV    453mV      499.4mV
402ps     471mV      453mV      507.9mV
521ps     492.6mV    452.8mV    763.7mV
600ps     671.1mV    463.3mV    845.9mV
642ps     739.2mV    497.4mV    871.4mV
693ps     794.6mV    594.6mV    893.6mV
812ps     859.7mV    761.1mV    919.8mV
910ps     881.7mV    819mV      926.5mV
1.041ns   894.4mV    851.1mV    929mV
50ns      900mV      870mV      930mV
[Falling Waveform]
R_fixture= 50.000
V_fixture= 0.900
V_fixture_min= 0.870
V_fixture_max= 0.930
|time   V(typ)   V(min)   V(max)
0s        900mV      870mV      930mV
1.253ns   900.7mV    870.7mV    914.1mV
1.96ns    880.2mV    869.5mV    680mV
2.504ns   791.3mV    860mV      550mV
3.311ns   605.4mV    802.2mV    517mV
3.919ns   535.9mV    727.1mV    509.1mV
5.002ns   497.1mV    586.3mV    503.1mV
5.812ns   486.3mV    530.2mV    501.2mV
9.368ns   473.3mV    467.4mV    499.5mV
50ns      471.4mV    453mV      499.4mV
[Falling Waveform]
R_fixture= 50.000
V_fixture= 0.0
V_fixture_min= 0.0
V_fixture_max= 0.0
|time   V(typ)   V(min)   V(max)
0s        418.3mV    395.7mV    432.9mV
396ps     420mV      395.9mV    424mV
437ps     419.8mV    396.8mV    378mV
496ps     406.5mV    398.1mV    257.4mV
574ps     308.2mV    390.3mV    130.2mV
669ps     152.3mV    309.7mV    58.87mV
771ps     66.31mV    173.1mV    26.19mV
921ps     21.04mV    54.86mV    8.718mV
1.15ns    4.482mV    10.69mV    2.474mV
50ns      1.175uV    6.313uV    542.9nV
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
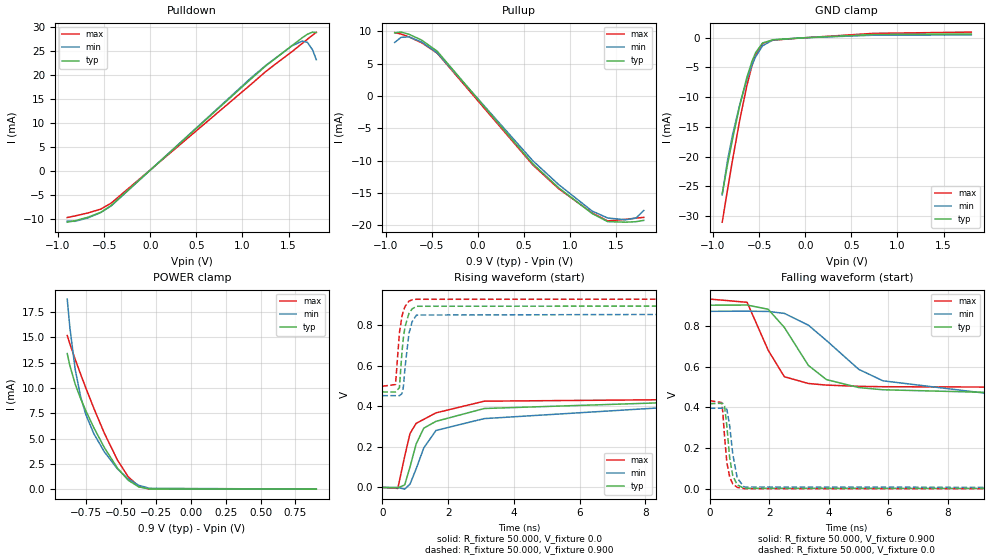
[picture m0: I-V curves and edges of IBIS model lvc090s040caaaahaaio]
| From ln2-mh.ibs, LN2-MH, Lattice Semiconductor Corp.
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|   Model lvc090s040caaaahaaio
[Model] lvc090s040caaaahaaio
| Clamp models do not include dynamic input termination. Please refer to
| the lvc090axxxcaaaahaain model for input termination.
Model_type I/O
Polarity   Non-Inverting
Enable   Active-Low
Vinl =  0.300V
Vinh =  0.600V
Vmeas =  0.500V
Cref =  0.0F
Rref =  1.000M
Vref =  0.0V
C_comp   2.000pF   1.500pF   2.500pF
[Temperature Range]   25.000   0.125k   -40.000
[Voltage Range]   0.900V   0.870V   0.930V
[C Comp Corner]
C_comp   2.000pF   1.500pF   2.500pF
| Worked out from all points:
|   slope of the pulldown table from 0 to 0.135 V, typ, clamps not added: 57.8 ohm
|   slope of the pullup table from 0 to 0.135 V, typ, clamps not added: 56.3 ohm
|   GND clamp passes 1 mA (typ) near -0.47 V on its own axis
|   POWER clamp passes 1 mA (typ) near -0.46 V on its own axis
|   rising waveform, R_fixture 50.000, V_fixture 0.0: 20-80 % time 1.02ns typ, 1.29ns min, 783ps max; typ from 0 V to 0.418 V
|   rising waveform, R_fixture 50.000, V_fixture 0.900: 20-80 % time 166ps typ, 183ps min, 158ps max; typ from 0.471 V to 0.9 V
|   falling waveform, R_fixture 50.000, V_fixture 0.900: 20-80 % time 1.26ns typ, 2.24ns min, 719ps max; typ from 0.9 V to 0.471 V
|   falling waveform, R_fixture 50.000, V_fixture 0.0: 20-80 % time 184ps typ, 210ps min, 168ps max; typ from 0.418 V to 0 V
[Pulldown]
|Voltage   I(typ)   I(min)   I(max)
-900mV    -10.75mA   -10.54mA   -9.775mA
-816mV    -10.45mA   -10.57mA   -9.448mA
-676mV    -9.72mA    -9.855mA   -8.831mA
-536mV    -8.693mA   -8.733mA   -8.021mA
-424mV    -7.279mA   -7.362mA   -6.782mA
1.088V    19.03mA    19.24mA    17.9mA
1.256V    21.87mA    21.97mA    20.71mA
1.536V    26.04mA    25.99mA    24.78mA
1.648V    27.68mA    26.99mA    26.51mA
1.704V    28.41mA    26.71mA    27.38mA
1.76V     28.86mA    25.14mA    28.24mA
1.8V      28.78mA    23.11mA    28.82mA
[Pullup]
|Voltage   I(typ)   I(min)   I(max)
-900mV    9.8mA      8.3mA      9.818mA
-832mV    9.902mA    9.088mA    9.597mA
-748mV    9.581mA    9.168mA    9.17mA
-608mV    8.661mA    8.366mA    8.248mA
-440mV    6.952mA    6.69mA     6.645mA
596mV     -10.45mA   -9.975mA   -10.62mA
876mV     -14.15mA   -13.66mA   -14.3mA
1.24V     -18.15mA   -17.77mA   -18.06mA
1.408V    -19.4mA    -18.84mA   -19.29mA
1.604V    -19.49mA   -19.12mA   -19.05mA
1.716V    -19.41mA   -18.84mA   -18.86mA
1.8V      -19.21mA   -17.68mA   -18.75mA
[GND_clamp]
|Voltage   I(typ)   I(min)   I(max)
-900mV    -26.23mA   -26.42mA   -31.01mA
-843mV    -21.35mA   -20.64mA   -25.59mA
-786mV    -16.88mA   -16.2mA    -20.37mA
-710mV    -11.41mA   -11.24mA   -13.83mA
-634mV    -6.729mA   -7.102mA   -8.134mA
-577mV    -3.961mA   -4.589mA   -4.707mA
-539mV    -2.551mA   -3.235mA   -2.953mA
-463mV    -890.5uA   -1.367mA   -946.5uA
-349mV    -352.6uA   -378.2uA   -421.6uA
-45mV     -42.8uA    -36.37uA   -52.77uA
734mV     527.5uA    410.9uA    719.1uA
1.8V      610uA      464.4uA    937.2uA
[POWER_clamp]
|Voltage   I(typ)   I(min)   I(max)
-886mV    13.4mA     18.79mA    15.19mA
-867mV    12.2mA     15.95mA    14.36mA
-829mV    10.39mA    11.85mA    12.84mA
-791mV    8.986mA    9.193mA    11.4mA
-753mV    7.76mA     7.389mA    10.02mA
-696mV    6.096mA    5.502mA    8.018mA
-620mV    4.114mA    3.69mA     5.536mA
-525mV    2.063mA    1.993mA    2.854mA
-449mV    884.5uA    1.009mA    1.231mA
-373mV    221.5uA    379.3uA    279.5uA
-297mV    19.57uA    87.58uA    7.748uA
900mV     0A         0A         0A
[Ramp]
| variable   typ   min   max
dV/dt_r   0.251/1.019n   0.237/1.289n   0.260/0.783n
dV/dt_f   0.257/1.279n   0.250/2.251n   0.258/0.724n
R_load = 50.000
[Rising Waveform]
R_fixture= 50.000
V_fixture= 0.0
V_fixture_min= 0.0
V_fixture_max= 0.0
|time   V(typ)   V(min)   V(max)
0s        1.176uV    6.304uV    543.6nV
472ps     -2.56mV    -267.7uV   -5.05mV
681ps     12.29mV    -8.753mV   153.2mV
843ps     100.9mV    15.97mV    266.2mV
1.029ns   214.3mV    91.5mV     316.2mV
1.262ns   292.7mV    195.1mV    336.2mV
1.633ns   326.2mV    281.2mV    368.1mV
3.099ns   389.6mV    339.7mV    425.7mV
8.502ns   418mV      393.5mV    432.9mV
50ns      418.3mV    395.7mV    432.9mV
[Rising Waveform]
R_fixture= 50.000
V_fixture= 0.900
V_fixture_min= 0.870
V_fixture_max= 0.930
|time   V(typ)   V(min)   V(max)
0s        471.4mV    453mV      499.4mV
402ps     471mV      453mV      507.9mV
521ps     492.6mV    452.8mV    763.7mV
600ps     671.1mV    463.3mV    845.9mV
642ps     739.2mV    497.4mV    871.4mV
693ps     794.6mV    594.6mV    893.6mV
812ps     859.7mV    761.1mV    919.8mV
910ps     881.7mV    819mV      926.5mV
1.041ns   894.4mV    851.1mV    929mV
50ns      900mV      870mV      930mV
[Falling Waveform]
R_fixture= 50.000
V_fixture= 0.900
V_fixture_min= 0.870
V_fixture_max= 0.930
|time   V(typ)   V(min)   V(max)
0s        900mV      870mV      930mV
1.253ns   900.7mV    870.7mV    914.1mV
1.96ns    880.2mV    869.5mV    680mV
2.504ns   791.3mV    860mV      550mV
3.311ns   605.4mV    802.2mV    517mV
3.919ns   535.9mV    727.1mV    509.1mV
5.002ns   497.1mV    586.3mV    503.1mV
5.812ns   486.3mV    530.2mV    501.2mV
9.368ns   473.3mV    467.4mV    499.5mV
50ns      471.4mV    453mV      499.4mV
[Falling Waveform]
R_fixture= 50.000
V_fixture= 0.0
V_fixture_min= 0.0
V_fixture_max= 0.0
|time   V(typ)   V(min)   V(max)
0s        418.3mV    395.7mV    432.9mV
396ps     420mV      395.9mV    424mV
437ps     419.8mV    396.8mV    378mV
496ps     406.5mV    398.1mV    257.4mV
574ps     308.2mV    390.3mV    130.2mV
669ps     152.3mV    309.7mV    58.87mV
771ps     66.31mV    173.1mV    26.19mV
921ps     21.04mV    54.86mV    8.718mV
1.15ns    4.482mV    10.69mV    2.474mV
50ns      1.175uV    6.313uV    542.9nV
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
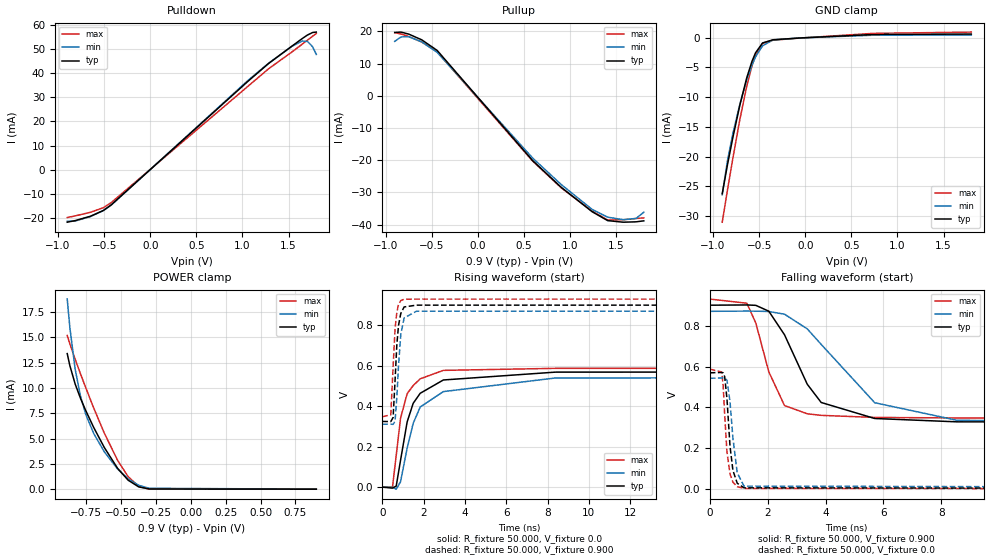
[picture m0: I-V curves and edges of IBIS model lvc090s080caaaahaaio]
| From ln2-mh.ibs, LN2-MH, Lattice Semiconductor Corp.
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|   Model lvc090s080caaaahaaio
[Model] lvc090s080caaaahaaio
| Clamp models do not include dynamic input termination. Please refer to
| the lvc090axxxcaaaahaain model for input termination.
Model_type I/O
Polarity   Non-Inverting
Enable   Active-Low
Vinl =  0.300V
Vinh =  0.600V
Vmeas =  0.500V
Cref =  0.0F
Rref =  1.000M
Vref =  0.0V
C_comp   2.000pF   1.500pF   2.500pF
[Temperature Range]   25.000   0.125k   -40.000
[Voltage Range]   0.900V   0.870V   0.930V
[C Comp Corner]
C_comp   2.000pF   1.500pF   2.500pF
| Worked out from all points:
|   slope of the pulldown table from 0 to 0.135 V, typ, clamps not added: 29 ohm
|   slope of the pullup table from 0 to 0.135 V, typ, clamps not added: 28.8 ohm
|   GND clamp passes 1 mA (typ) near -0.47 V on its own axis
|   POWER clamp passes 1 mA (typ) near -0.46 V on its own axis
|   rising waveform, R_fixture 50.000, V_fixture 0.0: 20-80 % time 894ps typ, 1.13ns min, 609ps max; typ from 0 V to 0.569 V
|   rising waveform, R_fixture 50.000, V_fixture 0.900: 20-80 % time 193ps typ, 208ps min, 177ps max; typ from 0.325 V to 0.9 V
|   falling waveform, R_fixture 50.000, V_fixture 0.900: 20-80 % time 1.26ns typ, 2.15ns min, 717ps max; typ from 0.9 V to 0.325 V
|   falling waveform, R_fixture 50.000, V_fixture 0.0: 20-80 % time 186ps typ, 214ps min, 167ps max; typ from 0.569 V to 0 V
[Pulldown]
|Voltage   I(typ)   I(min)   I(max)
-900mV    -21.71mA   -21.3mA    -19.79mA
-816mV    -21.07mA   -21.25mA   -19.13mA
-648mV    -19.24mA   -19.38mA   -17.61mA
-508mV    -16.87mA   -16.87mA   -15.72mA
-424mV    -14.56mA   -14.68mA   -13.63mA
1.06V     36.59mA    36.94mA    34.53mA
1.284V    43.96mA    44.05mA    41.77mA
1.536V    51.11mA    51.03mA    48.69mA
1.648V    54.24mA    53.2mA     51.93mA
1.704V    55.69mA    53.07mA    53.58mA
1.76V     56.74mA    50.85mA    55.21mA
1.8V      56.91mA    47.67mA    56.33mA
[Pullup]
|Voltage   I(typ)   I(min)   I(max)
-900mV    19.67mA    16.9mA     19.62mA
-832mV    19.79mA    18.29mA    19.2mA
-748mV    19.16mA    18.35mA    18.42mA
-608mV    17.4mA     16.76mA    16.71mA
-440mV    14.09mA    13.5mA     13.65mA
596mV     -20.15mA   -19.36mA   -20.31mA
904mV     -28.41mA   -27.54mA   -28.57mA
1.24V     -36.01mA   -35.29mA   -35.8mA
1.408V    -38.77mA   -37.7mA    -38.57mA
1.576V    -39.26mA   -38.47mA   -38.51mA
1.716V    -39.15mA   -38.1mA    -38.11mA
1.8V      -38.84mA   -36.16mA   -37.92mA
[GND_clamp]
|Voltage   I(typ)   I(min)   I(max)
-900mV    -26.23mA   -26.42mA   -31.01mA
-843mV    -21.35mA   -20.64mA   -25.59mA
-786mV    -16.88mA   -16.2mA    -20.37mA
-710mV    -11.41mA   -11.24mA   -13.83mA
-634mV    -6.729mA   -7.102mA   -8.134mA
-577mV    -3.961mA   -4.589mA   -4.707mA
-539mV    -2.551mA   -3.235mA   -2.953mA
-463mV    -890.5uA   -1.367mA   -946.5uA
-349mV    -352.6uA   -378.2uA   -421.6uA
-45mV     -42.8uA    -36.37uA   -52.77uA
734mV     527.5uA    410.9uA    719.1uA
1.8V      610uA      464.4uA    937.2uA
[POWER_clamp]
|Voltage   I(typ)   I(min)   I(max)
-886mV    13.4mA     18.79mA    15.19mA
-867mV    12.2mA     15.95mA    14.36mA
-829mV    10.39mA    11.85mA    12.84mA
-791mV    8.986mA    9.193mA    11.4mA
-753mV    7.76mA     7.389mA    10.02mA
-696mV    6.096mA    5.502mA    8.018mA
-620mV    4.114mA    3.69mA     5.536mA
-525mV    2.063mA    1.993mA    2.854mA
-449mV    884.5uA    1.009mA    1.231mA
-373mV    221.5uA    379.3uA    279.5uA
-297mV    19.57uA    87.58uA    7.748uA
900mV     0A         0A         0A
[Ramp]
| variable   typ   min   max
dV/dt_r   0.342/0.895n   0.326/1.130n   0.352/0.608n
dV/dt_f   0.345/1.263n   0.335/2.155n   0.349/0.718n
R_load = 50.000
[Rising Waveform]
R_fixture= 50.000
V_fixture= 0.0
V_fixture_min= 0.0
V_fixture_max= 0.0
|time   V(typ)   V(min)   V(max)
0s        748.2nV    4.058uV    349.5nV
494ps     -4.891mV   -929.8uV   504.4uV
675ps     5.181mV    -10.08mV   156.8mV
884ps     132.5mV    26.63mV    340.2mV
1.204ns   322.5mV    192.8mV    462.3mV
1.496ns   414.5mV    315.5mV    502.2mV
1.836ns   464mV      396.3mV    535.6mV
2.956ns   529.9mV    472.4mV    577.4mV
8.383ns   568.7mV    539.8mV    587.4mV
50ns      569.2mV    543mV      587.4mV
[Rising Waveform]
R_fixture= 50.000
V_fixture= 0.900
V_fixture_min= 0.870
V_fixture_max= 0.930
|time   V(typ)   V(min)   V(max)
0s        324.8mV    311.2mV    348mV
412ps     324.1mV    311.2mV    357.5mV
525ps     344.4mV    310.5mV    596.8mV
618ps     525.8mV    325.9mV    780.7mV
705ps     704.9mV    444.4mV    865.2mV
786ps     799.3mV    599.8mV    903.5mV
896ps     858.8mV    754.1mV    922.6mV
1.058ns   891mV      836.6mV    929mV
1.658ns   900mV      870mV      929.7mV
50ns      900mV      870mV      930mV
[Falling Waveform]
R_fixture= 50.000
V_fixture= 0.900
V_fixture_min= 0.870
V_fixture_max= 0.930
|time   V(typ)   V(min)   V(max)
0s        900mV      870mV      930mV
1.281ns   901.2mV    871.2mV    909.7mV
1.591ns   899.3mV    870.8mV    812.5mV
2.039ns   870.6mV    869.2mV    574mV
2.581ns   755.4mV    856mV      409.1mV
3.368ns   513.2mV    784.1mV    368.8mV
3.848ns   424.1mV    708.3mV    361.1mV
5.699ns   345.7mV    422.8mV    350.9mV
8.549ns   329.3mV    336.7mV    348.3mV
50ns      324.8mV    311.2mV    348mV
[Falling Waveform]
R_fixture= 50.000
V_fixture= 0.0
V_fixture_min= 0.0
V_fixture_max= 0.0
|time   V(typ)   V(min)   V(max)
0s        569.2mV    543mV      587.4mV
412ps     570.9mV    543.5mV    573.6mV
464ps     568.7mV    544.8mV    504.9mV
514ps     550.6mV    544.7mV    365mV
594ps     441.6mV    532.1mV    181.4mV
699ps     209.9mV    428.2mV    75mV
799ps     91.99mV    250.9mV    34.22mV
949ps     28.92mV    79.72mV    12.02mV
1.183ns   6.493mV    14.9mV     3.673mV
50ns      747.1nV    4.063uV    348.9nV
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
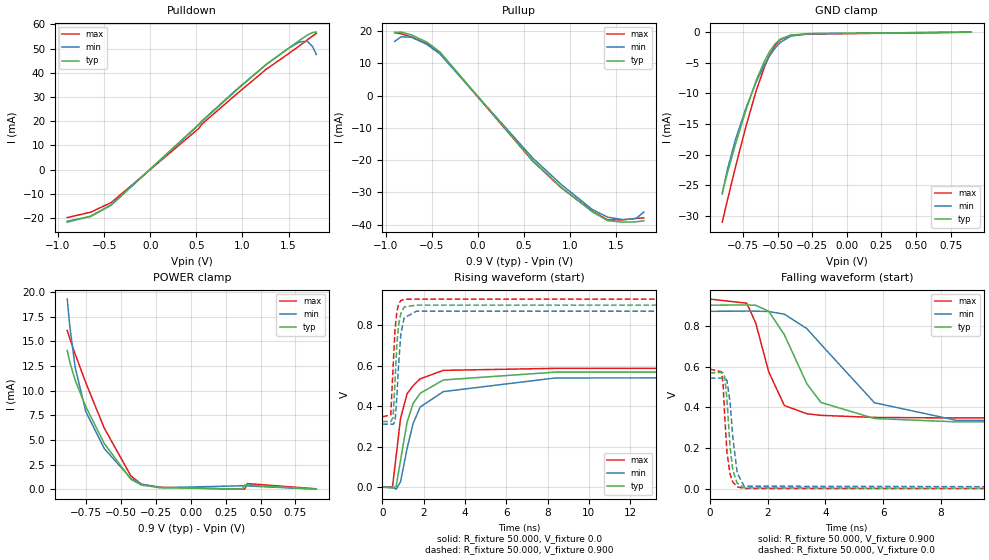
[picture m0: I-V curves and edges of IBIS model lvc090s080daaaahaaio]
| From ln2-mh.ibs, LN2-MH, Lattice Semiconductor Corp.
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|   Model lvc090s080daaaahaaio
[Model] lvc090s080daaaahaaio
| Clamp models do not include dynamic input termination. Please refer to
| the lvc090axxxdaaaahaain model for input termination.
Model_type I/O
Polarity   Non-Inverting
Enable   Active-Low
Vinl =  0.300V
Vinh =  0.600V
Vmeas =  0.500V
Cref =  0.0F
Rref =  1.000M
Vref =  0.0V
C_comp   2.000pF   1.500pF   2.500pF
[Temperature Range]   25.000   0.125k   -40.000
[Voltage Range]   0.900V   0.870V   0.930V
[C Comp Corner]
C_comp   2.000pF   1.500pF   2.500pF
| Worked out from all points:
|   slope of the pulldown table from 0 to 0.135 V, typ, clamps not added: 29 ohm
|   slope of the pullup table from 0 to 0.135 V, typ, clamps not added: 29.1 ohm
|   GND clamp passes 1 mA (typ) near -0.47 V on its own axis
|   POWER clamp passes 1 mA (typ) near -0.43 V on its own axis
|   rising waveform, R_fixture 50.000, V_fixture 0.0: 20-80 % time 894ps typ, 1.13ns min, 609ps max; typ from 0 V to 0.569 V
|   rising waveform, R_fixture 50.000, V_fixture 0.900: 20-80 % time 193ps typ, 208ps min, 177ps max; typ from 0.325 V to 0.9 V
|   falling waveform, R_fixture 50.000, V_fixture 0.900: 20-80 % time 1.26ns typ, 2.15ns min, 717ps max; typ from 0.9 V to 0.325 V
|   falling waveform, R_fixture 50.000, V_fixture 0.0: 20-80 % time 186ps typ, 214ps min, 167ps max; typ from 0.569 V to 0 V
[Pulldown]
|Voltage   I(typ)   I(min)   I(max)
-900mV    -21.71mA   -21.3mA    -19.79mA
-648mV    -19.24mA   -19.38mA   -17.61mA
-424mV    -14.56mA   -14.68mA   -13.63mA
528mV     18.76mA    18.54mA    17.08mA
556mV     19.75mA    19.98mA    18.69mA
948mV     33.26mA    33.52mA    31.6mA
1.256V    43.4mA     43.4mA     41.43mA
1.508V    50.4mA     50.33mA    48.13mA
1.62V     53.46mA    52.8mA     51.23mA
1.704V    55.62mA    53.01mA    53.61mA
1.76V     56.65mA    50.8mA     55.2mA
1.8V      56.82mA    47.61mA    56.29mA
[Pullup]
|Voltage   I(typ)   I(min)   I(max)
-900mV    19.57mA    16.84mA    19.56mA
-832mV    19.71mA    18.23mA    19.18mA
-720mV    18.85mA    18.12mA    18.21mA
-552mV    16.6mA     15.9mA     16.11mA
-412mV    13.6mA     12.97mA    13.37mA
596mV     -20.15mA   -19.36mA   -20.31mA
904mV     -28.41mA   -27.54mA   -28.57mA
1.24V     -36.01mA   -35.29mA   -35.8mA
1.408V    -38.77mA   -37.7mA    -38.57mA
1.576V    -39.26mA   -38.47mA   -38.51mA
1.716V    -39.15mA   -38.1mA    -38.11mA
1.8V      -38.84mA   -36.16mA   -37.92mA
[GND_clamp]
|Voltage   I(typ)   I(min)   I(max)
-900mV    -26.23mA   -26.42mA   -31.01mA
-862mV    -22.92mA   -22.36mA   -27.37mA
-805mV    -18.34mA   -17.59mA   -22.08mA
-729mV    -12.72mA   -12.41mA   -15.41mA
-653mV    -7.804mA   -8.056mA   -9.454mA
-596mV    -4.802mA   -5.365mA   -5.752mA
-558mV    -3.209mA   -3.878mA   -3.771mA
-520mV    -1.991mA   -2.661mA   -2.259mA
-482mV    -1.164mA   -1.727mA   -1.259mA
-406mV    -478.8uA   -668.8uA   -533.3uA
-273mV    -266uA     -238.6uA   -325.5uA
900mV     -290.6nA   1.13uA     -22.03uA
[POWER_clamp]
|Voltage   I(typ)   I(min)   I(max)
-886mV    14.08mA    19.3mA     16.11mA
-867mV    12.88mA    16.46mA    15.27mA
-829mV    11.06mA    12.36mA    13.71mA
-753mV    8.386mA    7.879mA    10.81mA
-620mV    4.627mA    4.114mA    6.183mA
-430mV    1.011mA    1.102mA    1.355mA
-354mV    411uA      505.3uA    502.8uA
-221mV    159.2uA    144.5uA    192.7uA
368mV     0A         343.5uA    0A
387mV     431.3uA    334.2uA    0A
406mV     418.8uA    324.3uA    563.7uA
900mV     0A         0A         34.92uA
[Ramp]
| variable   typ   min   max
dV/dt_r   0.342/0.895n   0.326/1.130n   0.352/0.608n
dV/dt_f   0.345/1.263n   0.335/2.155n   0.349/0.718n
R_load = 50.000
[Rising Waveform]
R_fixture= 50.000
V_fixture= 0.0
V_fixture_min= 0.0
V_fixture_max= 0.0
|time   V(typ)   V(min)   V(max)
0s        748.2nV    4.058uV    349.5nV
494ps     -4.891mV   -929.8uV   504.4uV
675ps     5.181mV    -10.08mV   156.8mV
884ps     132.5mV    26.63mV    340.2mV
1.204ns   322.5mV    192.8mV    462.3mV
1.496ns   414.5mV    315.5mV    502.2mV
1.836ns   464mV      396.3mV    535.6mV
2.956ns   529.9mV    472.4mV    577.4mV
8.377ns   568.7mV    539.8mV    587.4mV
50ns      569.2mV    543mV      587.4mV
[Rising Waveform]
R_fixture= 50.000
V_fixture= 0.900
V_fixture_min= 0.870
V_fixture_max= 0.930
|time   V(typ)   V(min)   V(max)
0s        324.8mV    311.2mV    348mV
412ps     324.1mV    311.2mV    357.5mV
525ps     344.4mV    310.5mV    596.8mV
618ps     525.8mV    325.9mV    780.7mV
705ps     704.9mV    444.4mV    865.2mV
786ps     799.3mV    599.8mV    903.5mV
896ps     858.8mV    754.1mV    922.6mV
1.058ns   891mV      836.6mV    929mV
1.658ns   900mV      870mV      929.7mV
50ns      900mV      870mV      930mV
[Falling Waveform]
R_fixture= 50.000
V_fixture= 0.900
V_fixture_min= 0.870
V_fixture_max= 0.930
|time   V(typ)   V(min)   V(max)
0s        900mV      870mV      930mV
1.281ns   901.2mV    871.2mV    909.7mV
1.591ns   899.3mV    870.8mV    812.5mV
2.039ns   870.6mV    869.2mV    574mV
2.581ns   755.4mV    856mV      409.1mV
3.359ns   515.4mV    785.3mV    369mV
3.848ns   424.1mV    708.3mV    361.1mV
5.699ns   345.7mV    422.8mV    350.9mV
8.529ns   329.3mV    336.9mV    348.3mV
50ns      324.8mV    311.2mV    348mV
[Falling Waveform]
R_fixture= 50.000
V_fixture= 0.0
V_fixture_min= 0.0
V_fixture_max= 0.0
|time   V(typ)   V(min)   V(max)
0s        569.2mV    543mV      587.4mV
412ps     570.9mV    543.5mV    573.6mV
464ps     568.7mV    544.8mV    504.9mV
514ps     550.6mV    544.7mV    365mV
594ps     441.6mV    532.1mV    181.4mV
699ps     209.9mV    428.2mV    75mV
799ps     91.99mV    250.9mV    34.22mV
949ps     28.92mV    79.72mV    12.02mV
1.185ns   6.423mV    14.7mV     3.65mV
50ns      747.1nV    4.063uV    348.9nV
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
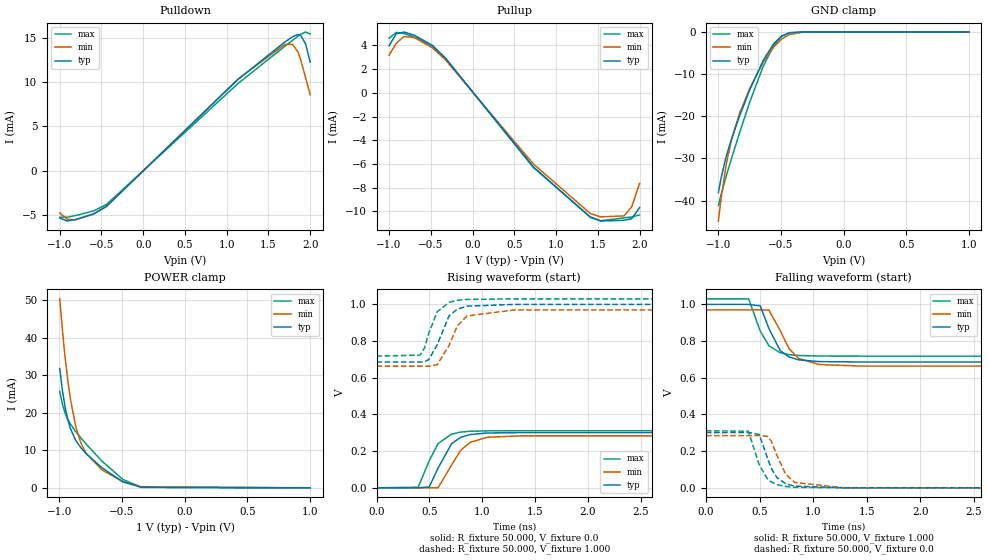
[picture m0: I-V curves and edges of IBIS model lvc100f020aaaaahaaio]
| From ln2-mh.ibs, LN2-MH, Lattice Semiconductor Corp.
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|   Model lvc100f020aaaaahaaio
[Model] lvc100f020aaaaahaaio
| Clamp models do not include dynamic input termination. Please refer to
| the lvc100axxxaaaaahaain model for input termination.
Model_type I/O
Polarity   Non-Inverting
Enable   Active-Low
Vinl =  0.350V
Vinh =  0.650V
Vmeas =  0.500V
Cref =  0.0F
Rref =  1.000M
Vref =  0.0V
C_comp   2.000pF   1.500pF   2.500pF
[Temperature Range]   25.000   0.125k   -40.000
[Voltage Range]   1.000V   0.970V   1.030V
[C Comp Corner]
C_comp   2.000pF   1.500pF   2.500pF
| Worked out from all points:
|   slope of the pulldown table from 0 to 0.15 V, typ, clamps not added: 108 ohm
|   slope of the pullup table from 0 to 0.15 V, typ, clamps not added: 110 ohm
|   GND clamp passes 1 mA (typ) near -0.50 V on its own axis
|   POWER clamp passes 1 mA (typ) near -0.45 V on its own axis
|   rising waveform, R_fixture 50.000, V_fixture 0.0: 20-80 % time 163ps typ, 183ps min, 151ps max; typ from 0 V to 0.301 V
|   rising waveform, R_fixture 50.000, V_fixture 1.000: 20-80 % time 133ps typ, 152ps min, 119ps max; typ from 0.686 V to 1 V
|   falling waveform, R_fixture 50.000, V_fixture 1.000: 20-80 % time 142ps typ, 166ps min, 131ps max; typ from 1 V to 0.686 V
|   falling waveform, R_fixture 50.000, V_fixture 0.0: 20-80 % time 124ps typ, 138ps min, 117ps max; typ from 0.301 V to 0 V
[Pulldown]
|Voltage   I(typ)   I(min)   I(max)
-1V       -5.336mA   -4.741mA   -5.244mA
-907mV    -5.666mA   -5.481mA   -5.236mA
-814mV    -5.51mA    -5.525mA   -5.056mA
-597mV    -4.881mA   -4.876mA   -4.537mA
-442mV    -4.029mA   -4.023mA   -3.816mA
1.139V    10.34mA    10.38mA    9.878mA
1.697V    14.54mA    14.27mA    14.06mA
1.79V     15.13mA    14.26mA    14.73mA
1.852V    15.37mA    13.43mA    15.18mA
1.883V    15.32mA    12.63mA    15.39mA
1.945V    14.33mA    10.51mA    15.66mA
2V        12.26mA    8.585mA    15.44mA
[Pullup]
|Voltage   I(typ)   I(min)   I(max)
-1V       3.975mA    3.175mA    4.603mA
-914mV    4.986mA    4.176mA    5.1mA
-821mV    5.129mA    4.75mA     4.999mA
-697mV    4.858mA    4.658mA    4.708mA
-480mV    3.999mA    3.793mA    3.924mA
-325mV    2.926mA    2.782mA    2.918mA
729mV     -6.251mA   -6.003mA   -6.3mA
1.411V    -10.5mA    -10.18mA   -10.47mA
1.535V    -10.81mA   -10.46mA   -10.79mA
1.814V    -10.75mA   -10.38mA   -10.54mA
1.907V    -10.61mA   -9.612mA   -10.47mA
2V        -9.681mA   -7.652mA   -10.3mA
[GND_clamp]
|Voltage   I(typ)   I(min)   I(max)
-1V       -38.12mA   -44.85mA   -41.21mA
-979mV    -34.68mA   -39.51mA   -38.64mA
-937mV    -29.43mA   -31.27mA   -34.13mA
-895mV    -25.33mA   -25.48mA   -29.97mA
-832mV    -20.01mA   -19.35mA   -24mA
-748mV    -13.6mA    -13.25mA   -16.46mA
-643mV    -6.759mA   -7.17mA    -8.178mA
-559mV    -2.781mA   -3.541mA   -3.248mA
-496mV    -972.8uA   -1.676mA   -1.012mA
-433mV    -198uA     -594.9uA   -143.9uA
-328mV    -6.321uA   -55.61uA   -1.827uA
1V        42.37pA    0A         0A
[POWER_clamp]
|Voltage   I(typ)   I(min)   I(max)
-995mV    31.81mA    50.36mA    25.7mA
-974mV    26.08mA    42.19mA    22.34mA
-953mV    21.65mA    35.04mA    20mA
-932mV    18.35mA    28.96mA    18.33mA
-911mV    15.92mA    23.9mA     17.05mA
-869mV    12.73mA    16.55mA    15.04mA
-827mV    10.71mA    11.99mA    13.31mA
-785mV    9.149mA    9.156mA    11.68mA
-659mV    5.357mA    4.783mA    7.128mA
-491mV    1.591mA    1.628mA    2.217mA
-344mV    125.7uA    266.7uA    146.2uA
1V        0A         0A         0A
[Ramp]
| variable   typ   min   max
dV/dt_r   0.181/0.163n   0.171/0.182n   0.187/0.151n
dV/dt_f   0.189/0.142n   0.184/0.167n   0.187/0.131n
R_load = 50.000
[Rising Waveform]
R_fixture= 50.000
V_fixture= 0.0
V_fixture_min= 0.0
V_fixture_max= 0.0
|time   V(typ)   V(min)   V(max)
0s        1.752uV    9.313uV    796.4nV
394ps     217.5uV    130.1uV    3.144mV
499ps     5.062mV    -107uV     147.9mV
583ps     108.5mV    720.8uV    241.2mV
710ps     240.2mV    123.7mV    293mV
794ps     274.6mV    203mV      303.6mV
884ps     290.2mV    247.5mV    308.2mV
1.044ns   298.8mV    275.3mV    310.5mV
1.374ns   301mV      283.7mV    311.1mV
10ns      301.2mV    284.3mV    311.2mV
[Rising Waveform]
R_fixture= 50.000
V_fixture= 1.000
V_fixture_min= 0.970
V_fixture_max= 1.030
|time   V(typ)   V(min)   V(max)
0s        685.7mV    662.8mV    717.8mV
411ps     685.7mV    662.9mV    723.4mV
453ps     686.8mV    663mV      760.5mV
496ps     700.1mV    662.8mV    845.1mV
574ps     779.4mV    670.9mV    959.3mV
686ps     937mV      775.7mV    1.011V
764ps     973.8mV    882.3mV    1.022V
856ps     990.3mV    937.1mV    1.027V
1.304ns   999.8mV    969.5mV    1.03V
10ns      1V         970mV      1.03V
[Falling Waveform]
R_fixture= 50.000
V_fixture= 1.000
V_fixture_min= 0.970
V_fixture_max= 1.030
|time   V(typ)   V(min)   V(max)
0s        1V         970mV      1.03V
399ps     999.9mV    970mV      1.03V
506ps     992.3mV    970.4mV    855.2mV
588ps     868mV      968.3mV    773.6mV
692ps     748.3mV    858mV      736.4mV
774ps     713.4mV    758.9mV    726mV
864ps     697.7mV    705.5mV    721.3mV
1.054ns   688.2mV    672.2mV    718.5mV
1.442ns   685.9mV    663.7mV    717.8mV
10ns      685.7mV    662.8mV    717.8mV
[Falling Waveform]
R_fixture= 50.000
V_fixture= 0.0
V_fixture_min= 0.0
V_fixture_max= 0.0
|time   V(typ)   V(min)   V(max)
0s        301.2mV    284.3mV    311.2mV
396ps     301.7mV    284.3mV    308.4mV
497ps     290.9mV    285.5mV    125.3mV
572ps     165.6mV    281.2mV    50.01mV
609ps     106.9mV    255mV      32.39mV
663ps     55.75mV    175.5mV    17.52mV
744ps     22.26mV    74mV       7.198mV
827ps     9.203mV    29.4mV     3.009mV
1.284ns   197.1uV    564.4uV    80.81uV
10ns      1.741uV    9.309uV    790nV
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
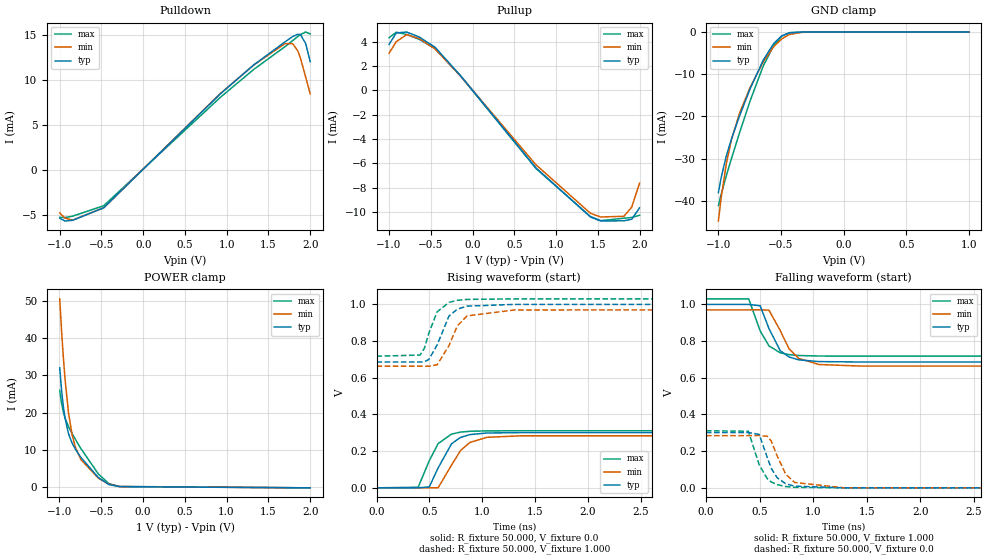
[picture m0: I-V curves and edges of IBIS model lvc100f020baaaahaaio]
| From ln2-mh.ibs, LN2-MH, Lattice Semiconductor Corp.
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|   Model lvc100f020baaaahaaio
[Model] lvc100f020baaaahaaio
| Clamp models do not include dynamic input termination. Please refer to
| the lvc100axxxbaaaahaain model for input termination.
Model_type I/O
Polarity   Non-Inverting
Enable   Active-Low
Vinl =  0.350V
Vinh =  0.650V
Vmeas =  0.500V
Cref =  0.0F
Rref =  1.000M
Vref =  0.0V
C_comp   2.000pF   1.500pF   2.500pF
[Temperature Range]   25.000   0.125k   -40.000
[Voltage Range]   1.000V   0.970V   1.030V
[C Comp Corner]
C_comp   2.000pF   1.500pF   2.500pF
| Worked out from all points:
|   slope of the pulldown table from 0 to 0.15 V, typ, clamps not added: 108 ohm
|   slope of the pullup table from 0 to 0.15 V, typ, clamps not added: 116 ohm
|   GND clamp passes 1 mA (typ) near -0.50 V on its own axis
|   POWER clamp passes 1 mA (typ) near -0.43 V on its own axis
|   rising waveform, R_fixture 50.000, V_fixture 0.0: 20-80 % time 163ps typ, 183ps min, 151ps max; typ from 0 V to 0.301 V
|   rising waveform, R_fixture 50.000, V_fixture 1.000: 20-80 % time 133ps typ, 152ps min, 119ps max; typ from 0.686 V to 1 V
|   falling waveform, R_fixture 50.000, V_fixture 1.000: 20-80 % time 142ps typ, 166ps min, 131ps max; typ from 1 V to 0.686 V
|   falling waveform, R_fixture 50.000, V_fixture 0.0: 20-80 % time 124ps typ, 138ps min, 117ps max; typ from 0.301 V to 0 V
[Pulldown]
|Voltage   I(typ)   I(min)   I(max)
-1V       -5.316mA   -4.722mA   -5.222mA
-938mV    -5.631mA   -5.306mA   -5.256mA
-845mV    -5.55mA    -5.529mA   -5.094mA
-473mV    -4.167mA   -4.157mA   -3.932mA
922mV     8.462mA    8.505mA    8.079mA
1.325V    11.7mA     11.69mA    11.2mA
1.697V    14.24mA    14.05mA    13.71mA
1.79V     14.84mA    14.05mA    14.39mA
1.852V    15.09mA    13.24mA    14.85mA
1.883V    15.05mA    12.46mA    15.06mA
1.945V    14.08mA    10.37mA    15.34mA
2V        12.06mA    8.472mA    15.13mA
[Pullup]
|Voltage   I(typ)   I(min)   I(max)
-1V       3.776mA    3.048mA    4.329mA
-914mV    4.723mA    4.003mA    4.777mA
-790mV    4.794mA    4.573mA    4.597mA
-635mV    4.372mA    4.247mA    4.181mA
-449mV    3.543mA    3.408mA    3.426mA
-139mV    1.17mA     1.138mA    1.145mA
760mV     -6.375mA   -6.122mA   -6.428mA
1.411V    -10.4mA    -10.1mA    -10.37mA
1.535V    -10.74mA   -10.41mA   -10.71mA
1.814V    -10.72mA   -10.35mA   -10.51mA
1.907V    -10.59mA   -9.588mA   -10.45mA
2V        -9.661mA   -7.635mA   -10.27mA
[GND_clamp]
|Voltage   I(typ)   I(min)   I(max)
-1V       -38.04mA   -44.76mA   -41.12mA
-979mV    -34.6mA    -39.43mA   -38.56mA
-937mV    -29.35mA   -31.19mA   -34.05mA
-895mV    -25.25mA   -25.4mA    -29.89mA
-832mV    -19.93mA   -19.28mA   -23.93mA
-748mV    -13.53mA   -13.18mA   -16.39mA
-643mV    -6.699mA   -7.109mA   -8.115mA
-559mV    -2.738mA   -3.494mA   -3.203mA
-496mV    -950.3uA   -1.644mA   -989.9uA
-433mV    -191.8uA   -578.6uA   -139.6uA
-328mV    -5.96uA    -52.93uA   -1.703uA
1V        0A         0A         0A
[POWER_clamp]
|Voltage   I(typ)   I(min)   I(max)
-995mV    32.01mA    50.49mA    25.97mA
-974mV    26.3mA     42.33mA    22.63mA
-953mV    21.89mA    35.2mA     20.31mA
-932mV    18.6mA     29.12mA    18.65mA
-890mV    14.38mA    19.99mA    16.32mA
-848mV    11.92mA    14.19mA    14.49mA
-806mV    10.18mA    10.62mA    12.83mA
-743mV    8.079mA    7.495mA    10.45mA
-533mV    2.652mA    2.481mA    3.608mA
-407mV    775.9uA    886.3uA    1.02mA
-281mV    222uA      236.7uA    263uA
2V        -103.7uA   -104.4uA   -104.8uA
[Ramp]
| variable   typ   min   max
dV/dt_r   0.181/0.163n   0.171/0.182n   0.187/0.151n
dV/dt_f   0.189/0.142n   0.184/0.167n   0.187/0.131n
R_load = 50.000
[Rising Waveform]
R_fixture= 50.000
V_fixture= 0.0
V_fixture_min= 0.0
V_fixture_max= 0.0
|time   V(typ)   V(min)   V(max)
0s        1.752uV    9.313uV    796.4nV
394ps     217.5uV    130.1uV    3.144mV
499ps     5.062mV    -107uV     147.9mV
583ps     108.5mV    720.8uV    241.2mV
710ps     240.2mV    123.7mV    293mV
794ps     274.6mV    203mV      303.6mV
884ps     290.2mV    247.5mV    308.2mV
1.044ns   298.8mV    275.3mV    310.5mV
1.374ns   301mV      283.7mV    311.1mV
10ns      301.2mV    284.3mV    311.2mV
[Rising Waveform]
R_fixture= 50.000
V_fixture= 1.000
V_fixture_min= 0.970
V_fixture_max= 1.030
|time   V(typ)   V(min)   V(max)
0s        685.7mV    662.8mV    717.8mV
411ps     685.7mV    662.9mV    723.4mV
453ps     686.8mV    663mV      760.5mV
496ps     700.1mV    662.8mV    845.1mV
574ps     779.4mV    670.9mV    959.3mV
686ps     937mV      775.7mV    1.011V
764ps     973.8mV    882.3mV    1.022V
856ps     990.3mV    937.1mV    1.027V
1.304ns   999.8mV    969.5mV    1.03V
10ns      1V         970mV      1.03V
[Falling Waveform]
R_fixture= 50.000
V_fixture= 1.000
V_fixture_min= 0.970
V_fixture_max= 1.030
|time   V(typ)   V(min)   V(max)
0s        1V         970mV      1.03V
399ps     999.9mV    970mV      1.03V
506ps     992.3mV    970.4mV    855.2mV
588ps     868mV      968.3mV    773.6mV
692ps     748.3mV    858mV      736.4mV
774ps     713.4mV    758.9mV    726mV
864ps     697.7mV    705.5mV    721.3mV
1.054ns   688.2mV    672.2mV    718.5mV
1.442ns   685.9mV    663.7mV    717.8mV
10ns      685.7mV    662.8mV    717.8mV
[Falling Waveform]
R_fixture= 50.000
V_fixture= 0.0
V_fixture_min= 0.0
V_fixture_max= 0.0
|time   V(typ)   V(min)   V(max)
0s        301.2mV    284.3mV    311.2mV
396ps     301.7mV    284.3mV    308.4mV
497ps     290.9mV    285.5mV    125.3mV
572ps     165.6mV    281.2mV    50.01mV
609ps     106.9mV    255mV      32.39mV
663ps     55.75mV    175.5mV    17.52mV
744ps     22.26mV    74mV       7.198mV
827ps     9.203mV    29.4mV     3.009mV
1.284ns   197.1uV    564.4uV    80.81uV
10ns      1.741uV    9.309uV    790nV
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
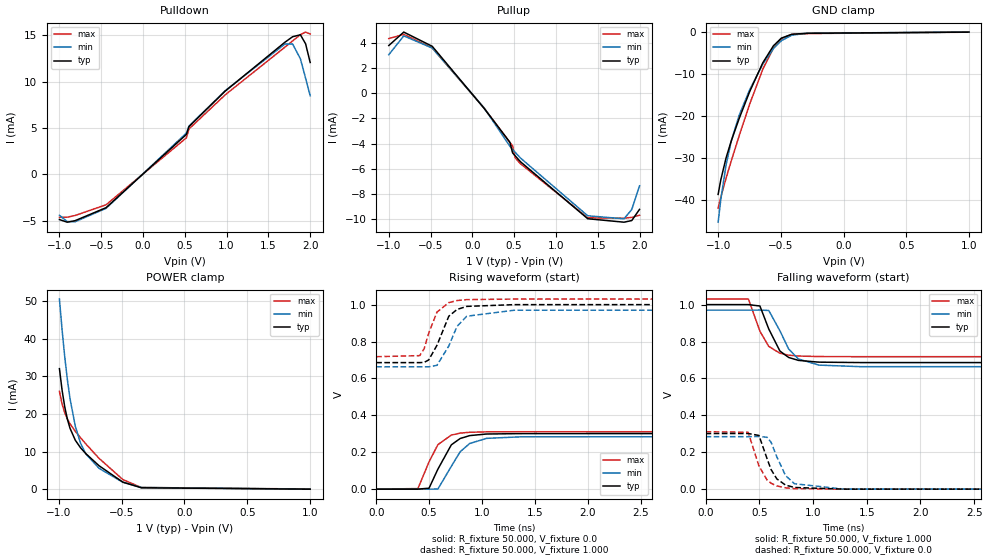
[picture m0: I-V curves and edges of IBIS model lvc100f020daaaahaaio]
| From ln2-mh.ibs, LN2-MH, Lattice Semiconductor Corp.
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|   Model lvc100f020daaaahaaio
[Model] lvc100f020daaaahaaio
| Clamp models do not include dynamic input termination. Please refer to
| the lvc100axxxdaaaahaain model for input termination.
Model_type I/O
Polarity   Non-Inverting
Enable   Active-Low
Vinl =  0.350V
Vinh =  0.650V
Vmeas =  0.500V
Cref =  0.0F
Rref =  1.000M
Vref =  0.0V
C_comp   2.000pF   1.500pF   2.500pF
[Temperature Range]   25.000   0.125k   -40.000
[Voltage Range]   1.000V   0.970V   1.030V
[C Comp Corner]
C_comp   2.000pF   1.500pF   2.500pF
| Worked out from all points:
|   slope of the pulldown table from 0 to 0.15 V, typ, clamps not added: 121 ohm
|   slope of the pullup table from 0 to 0.15 V, typ, clamps not added: 116 ohm
|   GND clamp passes 1 mA (typ) near -0.47 V on its own axis
|   POWER clamp passes 1 mA (typ) near -0.43 V on its own axis
|   rising waveform, R_fixture 50.000, V_fixture 0.0: 20-80 % time 163ps typ, 183ps min, 151ps max; typ from 0 V to 0.301 V
|   rising waveform, R_fixture 50.000, V_fixture 1.000: 20-80 % time 133ps typ, 152ps min, 119ps max; typ from 0.686 V to 1 V
|   falling waveform, R_fixture 50.000, V_fixture 1.000: 20-80 % time 142ps typ, 166ps min, 131ps max; typ from 1 V to 0.686 V
|   falling waveform, R_fixture 50.000, V_fixture 0.0: 20-80 % time 124ps typ, 138ps min, 117ps max; typ from 0.301 V to 0 V
[Pulldown]
|Voltage   I(typ)   I(min)   I(max)
-1V       -4.878mA   -4.415mA   -4.647mA
-907mV    -5.161mA   -5.09mA    -4.621mA
-814mV    -5.001mA   -5.115mA   -4.442mA
-442mV    -3.596mA   -3.668mA   -3.283mA
519mV     4.308mA    4.45mA     3.938mA
550mV     5.154mA    5.212mA    4.893mA
984mV     8.981mA    9.023mA    8.578mA
1.697V    14.24mA    14.05mA    13.71mA
1.79V     14.84mA    14.05mA    14.39mA
1.883V    15.05mA    12.46mA    15.06mA
1.945V    14.08mA    10.37mA    15.34mA
2V        12.06mA    8.472mA    15.13mA
[Pullup]
|Voltage   I(typ)   I(min)   I(max)
-1V       3.776mA    3.048mA    4.329mA
-821mV    4.844mA    4.542mA    4.663mA
-480mV    3.714mA    3.577mA    3.582mA
140mV     -1.202mA   -1.162mA   -1.188mA
450mV     -3.912mA   -4.227mA   -3.921mA
481mV     -4.737mA   -4.461mA   -4.187mA
512mV     -4.974mA   -4.691mA   -5.136mA
574mV     -5.435mA   -5.14mA    -5.591mA
1.38V     -9.965mA   -9.73mA    -9.889mA
1.814V    -10.24mA   -9.97mA    -9.923mA
1.907V    -10.11mA   -9.236mA   -9.856mA
2V        -9.222mA   -7.355mA   -9.687mA
[GND_clamp]
|Voltage   I(typ)   I(min)   I(max)
-1V       -38.58mA   -45.18mA   -41.8mA
-979mV    -35.16mA   -39.86mA   -39.25mA
-937mV    -29.93mA   -31.65mA   -34.75mA
-895mV    -25.83mA   -25.87mA   -30.59mA
-832mV    -20.52mA   -19.76mA   -24.62mA
-748mV    -14.11mA   -13.66mA   -17.07mA
-643mV    -7.258mA   -7.574mA   -8.782mA
-559mV    -3.266mA   -3.933mA   -3.841mA
-496mV    -1.438mA   -2.052mA   -1.583mA
-412mV    -512.3uA   -729.3uA   -564.2uA
-286mV    -286.6uA   -261.9uA   -348.8uA
1V        -79.89nA   0A         -21.82uA
[POWER_clamp]
|Voltage   I(typ)   I(min)   I(max)
-995mV    32.01mA    50.49mA    25.97mA
-974mV    26.3mA     42.33mA    22.63mA
-953mV    21.89mA    35.2mA     20.31mA
-932mV    18.6mA     29.12mA    18.65mA
-911mV    16.18mA    24.08mA    17.37mA
-869mV    13.01mA    16.74mA    15.37mA
-827mV    10.99mA    12.19mA    13.65mA
-785mV    9.438mA    9.371mA    12.02mA
-680mV    6.228mA    5.537mA    8.194mA
-491mV    1.877mA    1.844mA    2.561mA
-344mV    370.5uA    455uA      446.7uA
1V        0A         0A         35.82uA
[Ramp]
| variable   typ   min   max
dV/dt_r   0.181/0.163n   0.171/0.182n   0.187/0.151n
dV/dt_f   0.189/0.142n   0.184/0.167n   0.187/0.131n
R_load = 50.000
[Rising Waveform]
R_fixture= 50.000
V_fixture= 0.0
V_fixture_min= 0.0
V_fixture_max= 0.0
|time   V(typ)   V(min)   V(max)
0s        1.752uV    9.313uV    796.4nV
394ps     217.5uV    130.1uV    3.144mV
499ps     5.062mV    -107uV     147.9mV
583ps     108.5mV    720.8uV    241.2mV
710ps     240.2mV    123.7mV    293mV
794ps     274.6mV    203mV      303.6mV
884ps     290.2mV    247.5mV    308.2mV
1.044ns   298.8mV    275.3mV    310.5mV
1.374ns   301mV      283.7mV    311.1mV
10ns      301.2mV    284.3mV    311.2mV
[Rising Waveform]
R_fixture= 50.000
V_fixture= 1.000
V_fixture_min= 0.970
V_fixture_max= 1.030
|time   V(typ)   V(min)   V(max)
0s        685.7mV    662.8mV    717.8mV
411ps     685.7mV    662.9mV    723.4mV
453ps     686.8mV    663mV      760.5mV
496ps     700.1mV    662.8mV    845.1mV
574ps     779.4mV    670.9mV    959.3mV
686ps     937mV      775.7mV    1.011V
764ps     973.8mV    882.3mV    1.022V
856ps     990.3mV    937.1mV    1.027V
1.304ns   999.8mV    969.5mV    1.03V
10ns      1V         970mV      1.03V
[Falling Waveform]
R_fixture= 50.000
V_fixture= 1.000
V_fixture_min= 0.970
V_fixture_max= 1.030
|time   V(typ)   V(min)   V(max)
0s        1V         970mV      1.03V
399ps     999.9mV    970mV      1.03V
506ps     992.3mV    970.4mV    855.2mV
588ps     868mV      968.3mV    773.6mV
692ps     748.3mV    858mV      736.4mV
774ps     713.4mV    758.9mV    726mV
864ps     697.7mV    705.5mV    721.3mV
1.054ns   688.2mV    672.2mV    718.5mV
1.442ns   685.9mV    663.7mV    717.8mV
10ns      685.7mV    662.8mV    717.8mV
[Falling Waveform]
R_fixture= 50.000
V_fixture= 0.0
V_fixture_min= 0.0
V_fixture_max= 0.0
|time   V(typ)   V(min)   V(max)
0s        301.2mV    284.3mV    311.2mV
396ps     301.7mV    284.3mV    308.4mV
497ps     290.9mV    285.5mV    125.3mV
572ps     165.6mV    281.2mV    50.01mV
609ps     106.9mV    255mV      32.39mV
663ps     55.75mV    175.5mV    17.52mV
744ps     22.26mV    74mV       7.198mV
827ps     9.203mV    29.4mV     3.009mV
1.284ns   197.1uV    564.4uV    80.81uV
10ns      1.741uV    9.309uV    790nV
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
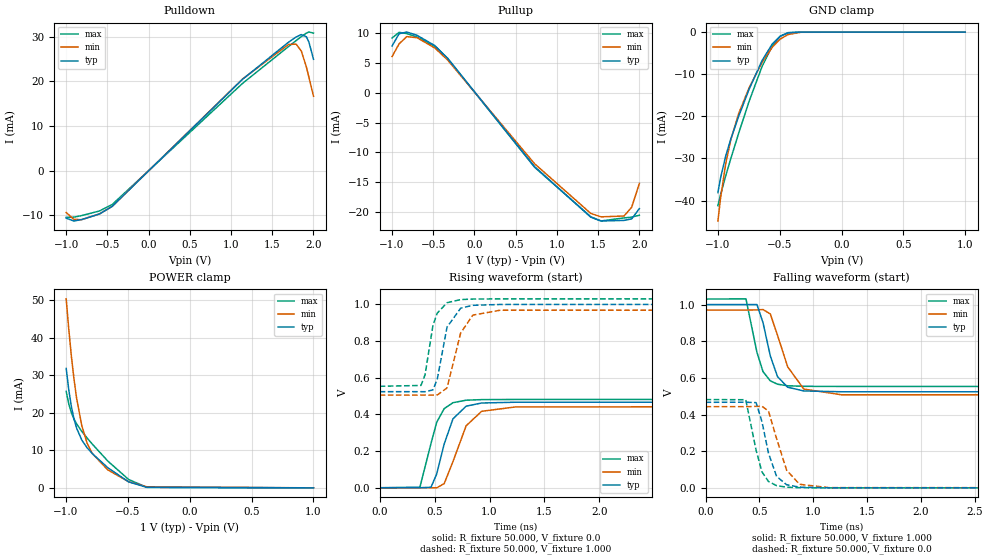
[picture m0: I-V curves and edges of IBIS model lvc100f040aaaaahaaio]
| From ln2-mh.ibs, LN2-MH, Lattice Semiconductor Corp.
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|   Model lvc100f040aaaaahaaio
[Model] lvc100f040aaaaahaaio
| Clamp models do not include dynamic input termination. Please refer to
| the lvc100axxxaaaaahaain model for input termination.
Model_type I/O
Polarity   Non-Inverting
Enable   Active-Low
Vinl =  0.350V
Vinh =  0.650V
Vmeas =  0.500V
Cref =  0.0F
Rref =  1.000M
Vref =  0.0V
C_comp   2.000pF   1.500pF   2.500pF
[Temperature Range]   25.000   0.125k   -40.000
[Voltage Range]   1.000V   0.970V   1.030V
[C Comp Corner]
C_comp   2.000pF   1.500pF   2.500pF
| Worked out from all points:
|   slope of the pulldown table from 0 to 0.15 V, typ, clamps not added: 54.8 ohm
|   slope of the pullup table from 0 to 0.15 V, typ, clamps not added: 55.6 ohm
|   GND clamp passes 1 mA (typ) near -0.50 V on its own axis
|   POWER clamp passes 1 mA (typ) near -0.45 V on its own axis
|   rising waveform, R_fixture 50.000, V_fixture 0.0: 20-80 % time 137ps typ, 168ps min, 121ps max; typ from 0 V to 0.467 V
|   rising waveform, R_fixture 50.000, V_fixture 1.000: 20-80 % time 98.1ps typ, 119ps min, 89.6ps max; typ from 0.524 V to 1 V
|   falling waveform, R_fixture 50.000, V_fixture 1.000: 20-80 % time 125ps typ, 166ps min, 106ps max; typ from 1 V to 0.524 V
|   falling waveform, R_fixture 50.000, V_fixture 0.0: 20-80 % time 114ps typ, 137ps min, 104ps max; typ from 0.467 V to 0 V
[Pulldown]
|Voltage   I(typ)   I(min)   I(max)
-1V       -10.61mA   -9.357mA   -10.43mA
-907mV    -11.25mA   -10.87mA   -10.39mA
-814mV    -10.93mA   -10.96mA   -10.04mA
-597mV    -9.684mA   -9.668mA   -9.009mA
-442mV    -7.977mA   -7.964mA   -7.56mA
1.139V    20.47mA    20.54mA    19.56mA
1.697V    28.78mA    28.28mA    27.81mA
1.79V     29.96mA    28.35mA    29.15mA
1.852V    30.49mA    26.82mA    30.03mA
1.914V    29.99mA    23.22mA    30.83mA
1.945V    28.78mA    20.88mA    31.06mA
2V        24.95mA    16.69mA    30.83mA
[Pullup]
|Voltage   I(typ)   I(min)   I(max)
-1V       7.88mA     6.096mA    9.215mA
-914mV    9.941mA    8.247mA    10.17mA
-821mV    10.22mA    9.449mA    9.957mA
-697mV    9.669mA    9.265mA    9.372mA
-480mV    7.939mA    7.529mA    7.795mA
-325mV    5.794mA    5.511mA    5.78mA
729mV     -12.39mA   -11.9mA    -12.49mA
1.411V    -20.87mA   -20.25mA   -20.82mA
1.535V    -21.52mA   -20.82mA   -21.51mA
1.814V    -21.42mA   -20.68mA   -21mA
1.907V    -21.16mA   -19.2mA    -20.87mA
2V        -19.43mA   -15.22mA   -20.55mA
[GND_clamp]
|Voltage   I(typ)   I(min)   I(max)
-1V       -38.12mA   -44.85mA   -41.21mA
-979mV    -34.68mA   -39.51mA   -38.64mA
-937mV    -29.43mA   -31.27mA   -34.13mA
-895mV    -25.33mA   -25.48mA   -29.97mA
-832mV    -20.01mA   -19.35mA   -24mA
-748mV    -13.6mA    -13.25mA   -16.46mA
-643mV    -6.759mA   -7.17mA    -8.178mA
-559mV    -2.781mA   -3.541mA   -3.248mA
-496mV    -972.8uA   -1.676mA   -1.012mA
-433mV    -198uA     -594.9uA   -143.9uA
-328mV    -6.321uA   -55.61uA   -1.827uA
1V        42.38pA    0A         0A
[POWER_clamp]
|Voltage   I(typ)   I(min)   I(max)
-995mV    31.81mA    50.36mA    25.7mA
-974mV    26.08mA    42.19mA    22.34mA
-953mV    21.65mA    35.04mA    20mA
-932mV    18.35mA    28.96mA    18.33mA
-911mV    15.92mA    23.9mA     17.05mA
-869mV    12.73mA    16.55mA    15.04mA
-827mV    10.71mA    11.99mA    13.31mA
-785mV    9.149mA    9.156mA    11.68mA
-659mV    5.357mA    4.783mA    7.128mA
-491mV    1.591mA    1.628mA    2.217mA
-344mV    125.7uA    266.7uA    146.2uA
1V        0A         0A         0A
[Ramp]
| variable   typ   min   max
dV/dt_r   0.280/0.137n   0.266/0.168n   0.289/0.121n
dV/dt_f   0.286/0.126n   0.279/0.166n   0.286/0.106n
R_load = 50.000
[Rising Waveform]
R_fixture= 50.000
V_fixture= 0.0
V_fixture_min= 0.0
V_fixture_max= 0.0
|time   V(typ)   V(min)   V(max)
0s        1.288uV    6.875uV    590.5nV
366ps     74.08uV    60.73uV    3.06mV
467ps     2.596mV    -195.8uV   241.4mV
519ps     75.52mV    -548.1uV   357.3mV
587ps     238.5mV    22.49mV    431.4mV
667ps     375.8mV    142.7mV    463.8mV
787ps     444.9mV    338mV      477.4mV
928ps     462.1mV    416.9mV    480.6mV
1.238ns   466.4mV    440.9mV    481.4mV
10ns      466.8mV    442.8mV    481.5mV
[Rising Waveform]
R_fixture= 50.000
V_fixture= 1.000
V_fixture_min= 0.970
V_fixture_max= 1.030
|time   V(typ)   V(min)   V(max)
0s        523.9mV    505.3mV    553.2mV
376ps     523.9mV    505.3mV    557.9mV
413ps     523.6mV    505.3mV    616.3mV
485ps     533.6mV    505mV      885.8mV
524ps     591.7mV    506mV      952.2mV
613ps     875.9mV    544.4mV    1.009V
737ps     979.2mV    844.1mV    1.026V
848ps     994.9mV    941.3mV    1.029V
1.097ns   999.5mV    968.1mV    1.03V
10ns      1V         970mV      1.03V
[Falling Waveform]
R_fixture= 50.000
V_fixture= 1.000
V_fixture_min= 0.970
V_fixture_max= 1.030
|time   V(typ)   V(min)   V(max)
0s        1V         970mV      1.03V
375ps     999.9mV    970mV      1.031V
477ps     1V         970.6mV    738.9mV
533ps     901.6mV    973mV      634.2mV
601ps     719.6mV    948.6mV    583.6mV
668ps     606.2mV    832mV      565.5mV
762ps     549mV      660.3mV    556.9mV
912ps     528.7mV    538.8mV    553.9mV
1.262ns   524.2mV    507.7mV    553.2mV
10ns      523.9mV    505.2mV    553.2mV
[Falling Waveform]
R_fixture= 50.000
V_fixture= 0.0
V_fixture_min= 0.0
V_fixture_max= 0.0
|time   V(typ)   V(min)   V(max)
0s        466.7mV    442.7mV    481.5mV
373ps     467.2mV    442.8mV    480.8mV
469ps     464.8mV    444.3mV    205.6mV
523ps     362mV      445.1mV    87.56mV
584ps     189mV      419.2mV    34.59mV
659ps     62.71mV    269.2mV    12.08mV
752ps     16.97mV    96.69mV    3.602mV
872ps     3.963mV    19.32mV    862.9uV
1.142ns   287.8uV    1.336mV    77.25uV
10ns      1.284uV    6.883uV    588nV
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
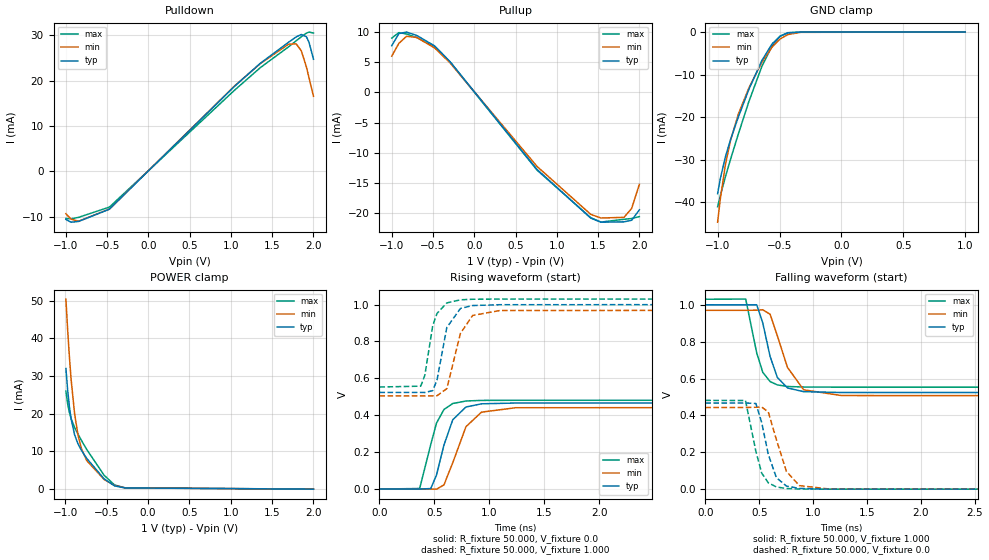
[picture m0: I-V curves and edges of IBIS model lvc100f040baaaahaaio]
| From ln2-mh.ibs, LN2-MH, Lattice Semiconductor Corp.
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|   Model lvc100f040baaaahaaio
[Model] lvc100f040baaaahaaio
| Clamp models do not include dynamic input termination. Please refer to
| the lvc100axxxbaaaahaain model for input termination.
Model_type I/O
Polarity   Non-Inverting
Enable   Active-Low
Vinl =  0.350V
Vinh =  0.650V
Vmeas =  0.500V
Cref =  0.0F
Rref =  1.000M
Vref =  0.0V
C_comp   2.000pF   1.500pF   2.500pF
[Temperature Range]   25.000   0.125k   -40.000
[Voltage Range]   1.000V   0.970V   1.030V
[C Comp Corner]
C_comp   2.000pF   1.500pF   2.500pF
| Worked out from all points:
|   slope of the pulldown table from 0 to 0.15 V, typ, clamps not added: 54.8 ohm
|   slope of the pullup table from 0 to 0.15 V, typ, clamps not added: 57.2 ohm
|   GND clamp passes 1 mA (typ) near -0.50 V on its own axis
|   POWER clamp passes 1 mA (typ) near -0.43 V on its own axis
|   rising waveform, R_fixture 50.000, V_fixture 0.0: 20-80 % time 137ps typ, 168ps min, 121ps max; typ from 0 V to 0.467 V
|   rising waveform, R_fixture 50.000, V_fixture 1.000: 20-80 % time 98.1ps typ, 119ps min, 89.6ps max; typ from 0.524 V to 1 V
|   falling waveform, R_fixture 50.000, V_fixture 1.000: 20-80 % time 125ps typ, 166ps min, 106ps max; typ from 1 V to 0.524 V
|   falling waveform, R_fixture 50.000, V_fixture 0.0: 20-80 % time 114ps typ, 137ps min, 104ps max; typ from 0.467 V to 0 V
[Pulldown]
|Voltage   I(typ)   I(min)   I(max)
-1V       -10.59mA   -9.338mA   -10.4mA
-938mV    -11.21mA   -10.54mA   -10.46mA
-845mV    -11.04mA   -10.99mA   -10.14mA
-473mV    -8.341mA   -8.309mA   -7.884mA
1.046V    18.82mA    18.9mA     17.96mA
1.356V    23.86mA    23.78mA    22.9mA
1.697V    28.48mA    28.06mA    27.47mA
1.79V     29.68mA    28.14mA    28.81mA
1.852V    30.21mA    26.63mA    29.7mA
1.914V    29.72mA    23.06mA    30.5mA
1.945V    28.54mA    20.74mA    30.74mA
2V        24.75mA    16.58mA    30.53mA
[Pullup]
|Voltage   I(typ)   I(min)   I(max)
-1V       7.682mA    5.969mA    8.941mA
-914mV    9.679mA    8.073mA    9.847mA
-821mV    9.932mA    9.241mA    9.621mA
-697mV    9.376mA    9.044mA    9.029mA
-480mV    7.654mA    7.313mA    7.453mA
-294mV    5.051mA    4.857mA    4.992mA
760mV     -12.74mA   -12.24mA   -12.85mA
1.411V    -20.77mA   -20.16mA   -20.72mA
1.535V    -21.45mA   -20.76mA   -21.43mA
1.814V    -21.39mA   -20.65mA   -20.97mA
1.907V    -21.13mA   -19.18mA   -20.84mA
2V        -19.41mA   -15.21mA   -20.53mA
[GND_clamp]
|Voltage   I(typ)   I(min)   I(max)
-1V       -38.04mA   -44.76mA   -41.12mA
-979mV    -34.6mA    -39.43mA   -38.56mA
-937mV    -29.35mA   -31.19mA   -34.05mA
-895mV    -25.25mA   -25.4mA    -29.89mA
-832mV    -19.93mA   -19.28mA   -23.93mA
-748mV    -13.53mA   -13.18mA   -16.39mA
-643mV    -6.699mA   -7.109mA   -8.115mA
-559mV    -2.738mA   -3.494mA   -3.203mA
-496mV    -950.2uA   -1.644mA   -989.9uA
-433mV    -191.7uA   -578.6uA   -139.6uA
-328mV    -5.96uA    -52.93uA   -1.703uA
1V        0A         0A         0A
[POWER_clamp]
|Voltage   I(typ)   I(min)   I(max)
-995mV    32.01mA    50.49mA    25.97mA
-974mV    26.3mA     42.33mA    22.63mA
-953mV    21.89mA    35.2mA     20.31mA
-932mV    18.6mA     29.12mA    18.65mA
-890mV    14.38mA    19.99mA    16.32mA
-848mV    11.92mA    14.19mA    14.49mA
-806mV    10.18mA    10.62mA    12.83mA
-743mV    8.079mA    7.495mA    10.45mA
-533mV    2.652mA    2.481mA    3.608mA
-407mV    775.9uA    886.3uA    1.02mA
-281mV    222uA      236.7uA    263uA
2V        -103.7uA   -104.4uA   -104.8uA
[Ramp]
| variable   typ   min   max
dV/dt_r   0.280/0.137n   0.266/0.168n   0.289/0.121n
dV/dt_f   0.286/0.126n   0.279/0.166n   0.286/0.106n
R_load = 50.000
[Rising Waveform]
R_fixture= 50.000
V_fixture= 0.0
V_fixture_min= 0.0
V_fixture_max= 0.0
|time   V(typ)   V(min)   V(max)
0s        1.288uV    6.875uV    590.5nV
366ps     74.08uV    60.73uV    3.06mV
467ps     2.596mV    -195.8uV   241.4mV
519ps     75.52mV    -548.1uV   357.3mV
587ps     238.5mV    22.49mV    431.4mV
667ps     375.8mV    142.7mV    463.8mV
787ps     444.9mV    338mV      477.4mV
928ps     462.1mV    416.9mV    480.6mV
1.238ns   466.4mV    440.9mV    481.4mV
10ns      466.8mV    442.8mV    481.5mV
[Rising Waveform]
R_fixture= 50.000
V_fixture= 1.000
V_fixture_min= 0.970
V_fixture_max= 1.030
|time   V(typ)   V(min)   V(max)
0s        523.9mV    505.3mV    553.2mV
376ps     523.9mV    505.3mV    557.9mV
413ps     523.6mV    505.3mV    616.3mV
485ps     533.6mV    505mV      885.8mV
524ps     591.7mV    506mV      952.2mV
613ps     875.9mV    544.4mV    1.009V
737ps     979.2mV    844.1mV    1.026V
848ps     994.9mV    941.3mV    1.029V
1.097ns   999.5mV    968.1mV    1.03V
10ns      1V         970mV      1.03V
[Falling Waveform]
R_fixture= 50.000
V_fixture= 1.000
V_fixture_min= 0.970
V_fixture_max= 1.030
|time   V(typ)   V(min)   V(max)
0s        1V         970mV      1.03V
375ps     999.9mV    970mV      1.031V
477ps     1V         970.6mV    738.9mV
533ps     901.6mV    973mV      634.2mV
601ps     719.6mV    948.6mV    583.6mV
668ps     606.2mV    832mV      565.5mV
762ps     549mV      660.3mV    556.9mV
912ps     528.7mV    538.8mV    553.9mV
1.262ns   524.2mV    507.7mV    553.2mV
10ns      523.9mV    505.2mV    553.2mV
[Falling Waveform]
R_fixture= 50.000
V_fixture= 0.0
V_fixture_min= 0.0
V_fixture_max= 0.0
|time   V(typ)   V(min)   V(max)
0s        466.7mV    442.7mV    481.5mV
373ps     467.2mV    442.8mV    480.8mV
469ps     464.8mV    444.3mV    205.6mV
523ps     362mV      445.1mV    87.56mV
584ps     189mV      419.2mV    34.59mV
659ps     62.71mV    269.2mV    12.08mV
752ps     16.97mV    96.69mV    3.602mV
872ps     3.963mV    19.32mV    862.9uV
1.142ns   287.8uV    1.336mV    77.25uV
10ns      1.284uV    6.883uV    588nV
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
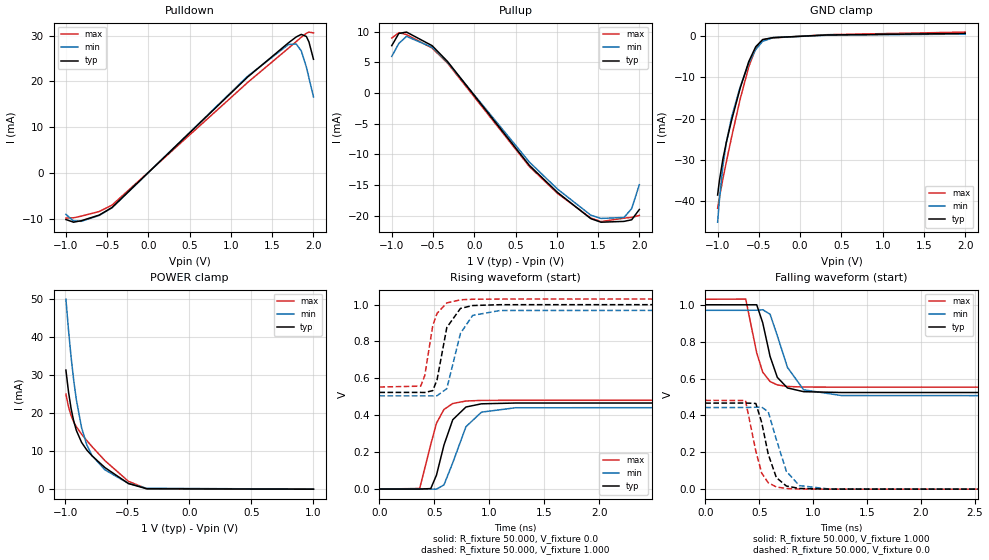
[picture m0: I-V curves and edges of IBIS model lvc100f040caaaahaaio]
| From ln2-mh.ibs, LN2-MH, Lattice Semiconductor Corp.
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|   Model lvc100f040caaaahaaio
[Model] lvc100f040caaaahaaio
| Clamp models do not include dynamic input termination. Please refer to
| the lvc100axxxcaaaahaain model for input termination.
Model_type I/O
Polarity   Non-Inverting
Enable   Active-Low
Vinl =  0.350V
Vinh =  0.650V
Vmeas =  0.500V
Cref =  0.0F
Rref =  1.000M
Vref =  0.0V
C_comp   2.000pF   1.500pF   2.500pF
[Temperature Range]   25.000   0.125k   -40.000
[Voltage Range]   1.000V   0.970V   1.030V
[C Comp Corner]
C_comp   2.000pF   1.500pF   2.500pF
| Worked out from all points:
|   slope of the pulldown table from 0 to 0.15 V, typ, clamps not added: 57.9 ohm
|   slope of the pullup table from 0 to 0.15 V, typ, clamps not added: 55.9 ohm
|   GND clamp passes 1 mA (typ) near -0.47 V on its own axis
|   POWER clamp passes 1 mA (typ) near -0.46 V on its own axis
|   rising waveform, R_fixture 50.000, V_fixture 0.0: 20-80 % time 137ps typ, 168ps min, 121ps max; typ from 0 V to 0.467 V
|   rising waveform, R_fixture 50.000, V_fixture 1.000: 20-80 % time 98.1ps typ, 119ps min, 89.6ps max; typ from 0.524 V to 1 V
|   falling waveform, R_fixture 50.000, V_fixture 1.000: 20-80 % time 125ps typ, 166ps min, 106ps max; typ from 1 V to 0.524 V
|   falling waveform, R_fixture 50.000, V_fixture 0.0: 20-80 % time 114ps typ, 137ps min, 104ps max; typ from 0.467 V to 0 V
[Pulldown]
|Voltage   I(typ)   I(min)   I(max)
-1V       -10.16mA   -9.031mA   -9.829mA
-907mV    -10.74mA   -10.48mA   -9.779mA
-814mV    -10.42mA   -10.55mA   -9.422mA
-597mV    -9.191mA   -9.269mA   -8.41mA
-442mV    -7.544mA   -7.61mA    -7.027mA
1.201V    20.92mA    21.1mA     19.73mA
1.697V    28.41mA    28.04mA    27.24mA
1.79V     29.68mA    28.16mA    28.67mA
1.852V    30.25mA    26.66mA    29.63mA
1.914V    29.79mA    23.1mA     30.49mA
1.945V    28.6mA     20.77mA    30.75mA
2V        24.82mA    16.61mA    30.57mA
[Pullup]
|Voltage   I(typ)   I(min)   I(max)
-1V       7.746mA    6.002mA    8.989mA
-914mV    9.742mA    8.109mA    9.857mA
-821mV    9.957mA    9.264mA    9.549mA
-511mV    7.742mA    7.475mA    7.347mA
-325mV    5.171mA    5.043mA    4.905mA
667mV     -11.77mA   -11.23mA   -11.96mA
1.008V    -16.18mA   -15.64mA   -16.34mA
1.411V    -20.46mA   -19.89mA   -20.36mA
1.535V    -21.04mA   -20.43mA   -20.94mA
1.814V    -20.91mA   -20.27mA   -20.38mA
1.907V    -20.65mA   -18.83mA   -20.25mA
2V        -18.97mA   -14.93mA   -19.94mA
[GND_clamp]
|Voltage   I(typ)   I(min)   I(max)
-1V       -38.58mA   -45.18mA   -41.8mA
-979mV    -35.16mA   -39.86mA   -39.25mA
-937mV    -29.93mA   -31.65mA   -34.75mA
-895mV    -25.83mA   -25.87mA   -30.59mA
-832mV    -20.52mA   -19.76mA   -24.62mA
-727mV    -12.62mA   -12.32mA   -15.28mA
-622mV    -6.113mA   -6.552mA   -7.373mA
-538mV    -2.537mA   -3.22mA    -2.933mA
-454mV    -801.3uA   -1.232mA   -848.9uA
-328mV    -333.7uA   -332.7uA   -402.2uA
323mV     301.4uA    251.4uA    374.9uA
2V        684.6uA    526.6uA    1.009mA
[POWER_clamp]
|Voltage   I(typ)   I(min)   I(max)
-995mV    31.28mA    49.94mA    24.97mA
-974mV    25.56mA    41.77mA    21.63mA
-953mV    21.15mA    34.64mA    19.32mA
-932mV    17.87mA    28.56mA    17.67mA
-911mV    15.45mA    23.52mA    16.41mA
-869mV    12.3mA     16.19mA    14.45mA
-827mV    10.3mA     11.65mA    12.77mA
-785mV    8.774mA    8.843mA    11.19mA
-680mV    5.655mA    5.063mA    7.48mA
-491mV    1.477mA    1.511mA    2.059mA
-344mV    103.3uA    232.5uA    114.2uA
1V        0A         0A         0A
[Ramp]
| variable   typ   min   max
dV/dt_r   0.280/0.137n   0.266/0.168n   0.289/0.121n
dV/dt_f   0.286/0.126n   0.279/0.166n   0.286/0.106n
R_load = 50.000
[Rising Waveform]
R_fixture= 50.000
V_fixture= 0.0
V_fixture_min= 0.0
V_fixture_max= 0.0
|time   V(typ)   V(min)   V(max)
0s        1.288uV    6.875uV    590.5nV
366ps     74.08uV    60.73uV    3.06mV
467ps     2.596mV    -195.8uV   241.4mV
519ps     75.52mV    -548.1uV   357.3mV
587ps     238.5mV    22.49mV    431.4mV
667ps     375.8mV    142.7mV    463.8mV
787ps     444.9mV    338mV      477.4mV
928ps     462.1mV    416.9mV    480.6mV
1.238ns   466.4mV    440.9mV    481.4mV
10ns      466.8mV    442.8mV    481.5mV
[Rising Waveform]
R_fixture= 50.000
V_fixture= 1.000
V_fixture_min= 0.970
V_fixture_max= 1.030
|time   V(typ)   V(min)   V(max)
0s        523.9mV    505.3mV    553.2mV
376ps     523.9mV    505.3mV    557.9mV
413ps     523.6mV    505.3mV    616.3mV
485ps     533.6mV    505mV      885.8mV
524ps     591.7mV    506mV      952.2mV
613ps     875.9mV    544.4mV    1.009V
737ps     979.2mV    844.1mV    1.026V
848ps     994.9mV    941.3mV    1.029V
1.097ns   999.5mV    968.1mV    1.03V
10ns      1V         970mV      1.03V
[Falling Waveform]
R_fixture= 50.000
V_fixture= 1.000
V_fixture_min= 0.970
V_fixture_max= 1.030
|time   V(typ)   V(min)   V(max)
0s        1V         970mV      1.03V
375ps     999.9mV    970mV      1.031V
477ps     1V         970.6mV    738.9mV
533ps     901.6mV    973mV      634.2mV
601ps     719.6mV    948.6mV    583.6mV
668ps     606.2mV    832mV      565.5mV
762ps     549mV      660.3mV    556.9mV
912ps     528.7mV    538.8mV    553.9mV
1.262ns   524.2mV    507.7mV    553.2mV
10ns      523.9mV    505.2mV    553.2mV
[Falling Waveform]
R_fixture= 50.000
V_fixture= 0.0
V_fixture_min= 0.0
V_fixture_max= 0.0
|time   V(typ)   V(min)   V(max)
0s        466.7mV    442.7mV    481.5mV
373ps     467.2mV    442.8mV    480.8mV
469ps     464.8mV    444.3mV    205.6mV
523ps     362mV      445.1mV    87.56mV
584ps     189mV      419.2mV    34.59mV
659ps     62.71mV    269.2mV    12.08mV
752ps     16.97mV    96.69mV    3.602mV
872ps     3.963mV    19.32mV    862.9uV
1.142ns   287.8uV    1.336mV    77.25uV
10ns      1.284uV    6.883uV    588nV
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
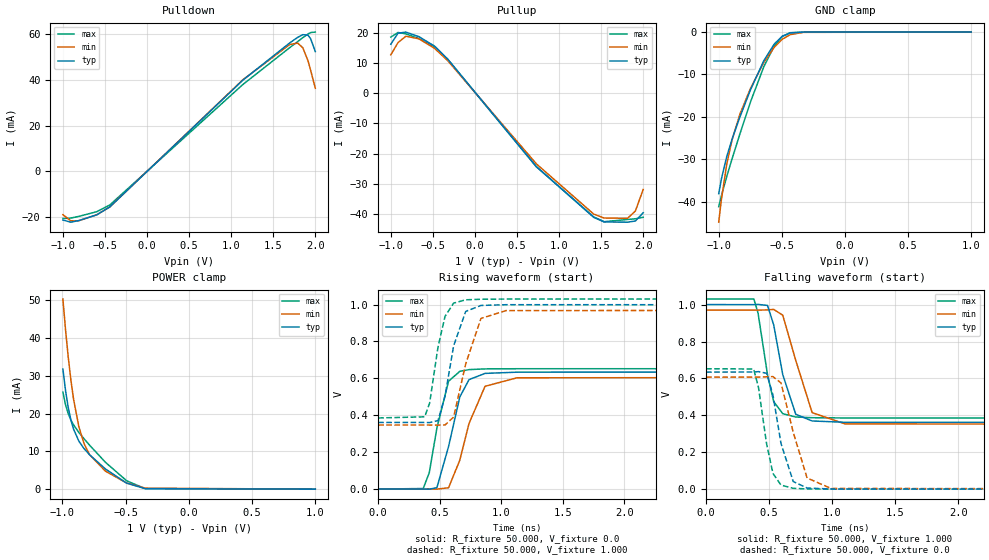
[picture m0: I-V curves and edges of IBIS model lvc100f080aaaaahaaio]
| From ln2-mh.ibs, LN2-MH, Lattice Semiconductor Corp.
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|   Model lvc100f080aaaaahaaio
[Model] lvc100f080aaaaahaaio
| Clamp models do not include dynamic input termination. Please refer to
| the lvc100axxxaaaaahaain model for input termination.
Model_type I/O
Polarity   Non-Inverting
Enable   Active-Low
Vinl =  0.350V
Vinh =  0.650V
Vmeas =  0.500V
Cref =  0.0F
Rref =  1.000M
Vref =  0.0V
C_comp   2.000pF   1.500pF   2.500pF
[Temperature Range]   25.000   0.125k   -40.000
[Voltage Range]   1.000V   0.970V   1.030V
[C Comp Corner]
C_comp   2.000pF   1.500pF   2.500pF
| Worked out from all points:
|   slope of the pulldown table from 0 to 0.15 V, typ, clamps not added: 28.2 ohm
|   slope of the pullup table from 0 to 0.15 V, typ, clamps not added: 28.5 ohm
|   GND clamp passes 1 mA (typ) near -0.50 V on its own axis
|   POWER clamp passes 1 mA (typ) near -0.45 V on its own axis
|   rising waveform, R_fixture 50.000, V_fixture 0.0: 20-80 % time 127ps typ, 153ps min, 110ps max; typ from 0 V to 0.634 V
|   rising waveform, R_fixture 50.000, V_fixture 1.000: 20-80 % time 109ps typ, 127ps min, 98.7ps max; typ from 0.361 V to 1 V
|   falling waveform, R_fixture 50.000, V_fixture 1.000: 20-80 % time 109ps typ, 140ps min, 93.6ps max; typ from 1 V to 0.361 V
|   falling waveform, R_fixture 50.000, V_fixture 0.0: 20-80 % time 103ps typ, 124ps min, 88.7ps max; typ from 0.634 V to 0 V
[Pulldown]
|Voltage   I(typ)   I(min)   I(max)
-1V       -21.25mA   -18.95mA   -20.6mA
-907mV    -22.22mA   -21.61mA   -20.43mA
-814mV    -21.54mA   -21.62mA   -19.71mA
-597mV    -19mA      -18.98mA   -17.63mA
-442mV    -15.54mA   -15.54mA   -14.68mA
1.139V    39.83mA    40.02mA    37.93mA
1.697V    56.14mA    55.41mA    54.08mA
1.79V     58.51mA    56.05mA    56.67mA
1.852V    59.72mA    53.98mA    58.41mA
1.914V    59.45mA    48.22mA    60.03mA
1.945V    57.9mA     44.12mA    60.63mA
2V        52.35mA    36.29mA    60.84mA
[Pullup]
|Voltage   I(typ)   I(min)   I(max)
-1V       16.19mA    12.7mA     18.55mA
-914mV    19.84mA    16.73mA    20.08mA
-821mV    20.2mA     18.83mA    19.6mA
-666mV    18.69mA    17.97mA    18.07mA
-480mV    15.57mA    14.82mA    15.25mA
-325mV    11.3mA     10.8mA     11.23mA
729mV     -24.23mA   -23.34mA   -24.33mA
1.411V    -41.05mA   -39.97mA   -40.89mA
1.535V    -42.58mA   -41.28mA   -42.49mA
1.814V    -42.66mA   -41.37mA   -41.76mA
1.907V    -42.26mA   -38.96mA   -41.53mA
2V        -39.53mA   -31.82mA   -41.03mA
[GND_clamp]
|Voltage   I(typ)   I(min)   I(max)
-1V       -38.12mA   -44.85mA   -41.21mA
-979mV    -34.68mA   -39.51mA   -38.64mA
-937mV    -29.43mA   -31.27mA   -34.13mA
-895mV    -25.33mA   -25.48mA   -29.97mA
-832mV    -20.01mA   -19.35mA   -24mA
-748mV    -13.6mA    -13.25mA   -16.46mA
-643mV    -6.759mA   -7.17mA    -8.178mA
-559mV    -2.781mA   -3.541mA   -3.248mA
-496mV    -972.8uA   -1.676mA   -1.012mA
-433mV    -198uA     -594.9uA   -143.9uA
-328mV    -6.321uA   -55.61uA   -1.827uA
1V        42.37pA    0A         0A
[POWER_clamp]
|Voltage   I(typ)   I(min)   I(max)
-995mV    31.81mA    50.36mA    25.7mA
-974mV    26.08mA    42.19mA    22.34mA
-953mV    21.65mA    35.04mA    20mA
-932mV    18.35mA    28.96mA    18.33mA
-911mV    15.92mA    23.9mA     17.05mA
-869mV    12.73mA    16.55mA    15.04mA
-827mV    10.71mA    11.99mA    13.31mA
-785mV    9.149mA    9.156mA    11.68mA
-659mV    5.357mA    4.783mA    7.128mA
-491mV    1.591mA    1.628mA    2.217mA
-344mV    125.7uA    266.7uA    146.2uA
1V        0A         0A         0A
[Ramp]
| variable   typ   min   max
dV/dt_r   0.381/0.127n   0.364/0.153n   0.391/0.110n
dV/dt_f   0.383/0.110n   0.374/0.140n   0.387/93.607p
R_load = 50.000
[Rising Waveform]
R_fixture= 50.000
V_fixture= 0.0
V_fixture_min= 0.0
V_fixture_max= 0.0
|time   V(typ)   V(min)   V(max)
0s        819.6nV    4.422uV    379.7nV
366ps     64.49uV    36.33uV    2.851mV
415ps     -589.6uV   68.71uV    88.76mV
477ps     7.551mV    -420.8uV   330.8mV
572ps     231.1mV    7.176mV    584.7mV
663ps     499mV      156.5mV    638mV
738ps     593.2mV    355.4mV    647.5mV
868ps     627mV      557mV      651.4mV
1.128ns   633.7mV    603.2mV    652.3mV
10ns      634.3mV    606.9mV    652.4mV
[Rising Waveform]
R_fixture= 50.000
V_fixture= 1.000
V_fixture_min= 0.970
V_fixture_max= 1.030
|time   V(typ)   V(min)   V(max)
0s        361mV      347.1mV    385.4mV
378ps     360.9mV    347.1mV    391.6mV
418ps     360.5mV    347.1mV    466.4mV
486ps     371mV      346.6mV    770.1mV
543ps     503.9mV    347.5mV    936mV
613ps     776.6mV    390.4mV    1.008V
711ps     963mV      678.2mV    1.026V
835ps     995.4mV    925mV      1.029V
1.039ns   999.4mV    967.6mV    1.03V
10ns      1V         970mV      1.03V
[Falling Waveform]
R_fixture= 50.000
V_fixture= 1.000
V_fixture_min= 0.970
V_fixture_max= 1.030
|time   V(typ)   V(min)   V(max)
0s        1V         970mV      1.03V
379ps     999.9mV    970mV      1.03V
412ps     1.001V     970mV      954mV
487ps     995.4mV    971.3mV    619.9mV
536ps     890.2mV    974mV      474.4mV
608ps     620.2mV    942.4mV    408.9mV
711ps     405.8mV    697.5mV    391mV
841ps     369.5mV    414.6mV    387.1mV
1.101ns   362.3mV    353.8mV    385.8mV
10ns      361mV      347.1mV    385.4mV
[Falling Waveform]
R_fixture= 50.000
V_fixture= 0.0
V_fixture_min= 0.0
V_fixture_max= 0.0
|time   V(typ)   V(min)   V(max)
0s        634.3mV    606.8mV    652.4mV
377ps     634.7mV    606.9mV    651.2mV
415ps     636.8mV    607.2mV    552.8mV
480ps     627.9mV    608.9mV    244.1mV
530ps     509.9mV    609.9mV    85.49mV
594ps     247.6mV    575.6mV    21.97mV
691ps     41.42mV    308.2mV    4.595mV
801ps     6.077mV    60.31mV    1.225mV
992ps     935.4uV    3.681mV    187.7uV
10ns      828.9nV    4.434uV    386.8nV
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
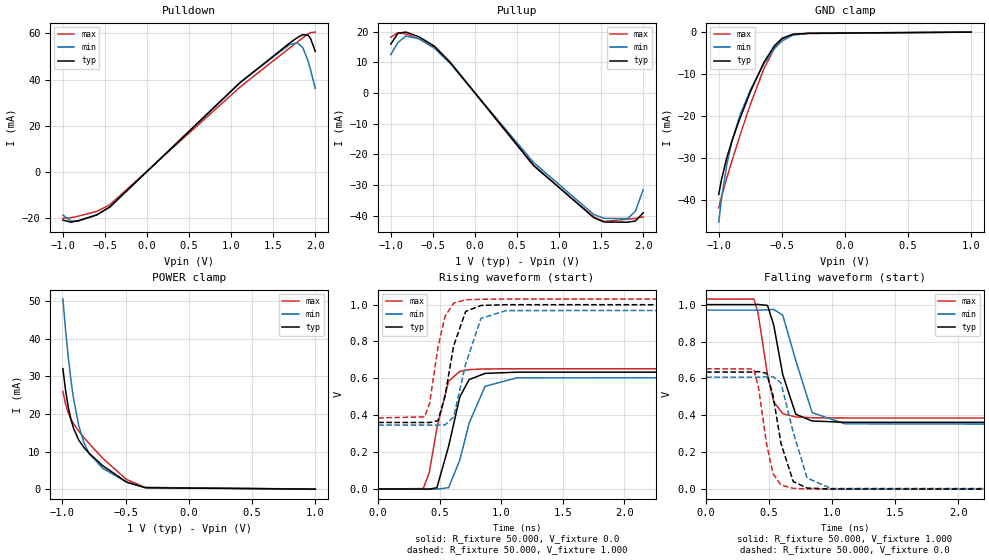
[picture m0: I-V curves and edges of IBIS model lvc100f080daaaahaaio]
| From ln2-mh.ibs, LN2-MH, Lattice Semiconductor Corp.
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|   Model lvc100f080daaaahaaio
[Model] lvc100f080daaaahaaio
| Clamp models do not include dynamic input termination. Please refer to
| the lvc100axxxdaaaahaain model for input termination.
Model_type I/O
Polarity   Non-Inverting
Enable   Active-Low
Vinl =  0.350V
Vinh =  0.650V
Vmeas =  0.500V
Cref =  0.0F
Rref =  1.000M
Vref =  0.0V
C_comp   2.000pF   1.500pF   2.500pF
[Temperature Range]   25.000   0.125k   -40.000
[Voltage Range]   1.000V   0.970V   1.030V
[C Comp Corner]
C_comp   2.000pF   1.500pF   2.500pF
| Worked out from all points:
|   slope of the pulldown table from 0 to 0.15 V, typ, clamps not added: 29 ohm
|   slope of the pullup table from 0 to 0.15 V, typ, clamps not added: 28.9 ohm
|   GND clamp passes 1 mA (typ) near -0.47 V on its own axis
|   POWER clamp passes 1 mA (typ) near -0.43 V on its own axis
|   rising waveform, R_fixture 50.000, V_fixture 0.0: 20-80 % time 127ps typ, 153ps min, 110ps max; typ from 0 V to 0.634 V
|   rising waveform, R_fixture 50.000, V_fixture 1.000: 20-80 % time 109ps typ, 127ps min, 98.7ps max; typ from 0.361 V to 1 V
|   falling waveform, R_fixture 50.000, V_fixture 1.000: 20-80 % time 109ps typ, 140ps min, 93.6ps max; typ from 1 V to 0.361 V
|   falling waveform, R_fixture 50.000, V_fixture 0.0: 20-80 % time 103ps typ, 124ps min, 88.7ps max; typ from 0.634 V to 0 V
[Pulldown]
|Voltage   I(typ)   I(min)   I(max)
-1V       -20.79mA   -18.63mA   -20mA
-907mV    -21.71mA   -21.21mA   -19.81mA
-814mV    -21.03mA   -21.21mA   -19.09mA
-597mV    -18.51mA   -18.58mA   -17.03mA
-442mV    -15.1mA    -15.19mA   -14.15mA
1.108V    38.7mA     38.91mA    36.84mA
1.697V    55.85mA    55.19mA    53.73mA
1.79V     58.22mA    55.85mA    56.33mA
1.852V    59.43mA    53.79mA    58.07mA
1.914V    59.19mA    48.07mA    59.7mA
1.945V    57.65mA    43.98mA    60.3mA
2V        52.16mA    36.18mA    60.54mA
[Pullup]
|Voltage   I(typ)   I(min)   I(max)
-1V       16mA       12.58mA    18.28mA
-914mV    19.57mA    16.56mA    19.76mA
-821mV    19.92mA    18.62mA    19.27mA
-666mV    18.4mA     17.75mA    17.72mA
-480mV    15.29mA    14.6mA     14.9mA
-294mV    10.05mA    9.674mA    9.945mA
698mV     -23.6mA    -22.67mA   -23.79mA
1.411V    -40.64mA   -39.61mA   -40.42mA
1.535V    -42.1mA    -40.89mA   -41.92mA
1.814V    -42.15mA   -40.97mA   -41.15mA
1.907V    -41.76mA   -38.58mA   -40.92mA
2V        -39.07mA   -31.52mA   -40.42mA
[GND_clamp]
|Voltage   I(typ)   I(min)   I(max)
-1V       -38.58mA   -45.18mA   -41.8mA
-979mV    -35.16mA   -39.86mA   -39.25mA
-937mV    -29.93mA   -31.65mA   -34.75mA
-895mV    -25.83mA   -25.87mA   -30.59mA
-832mV    -20.52mA   -19.76mA   -24.62mA
-748mV    -14.11mA   -13.66mA   -17.07mA
-643mV    -7.258mA   -7.574mA   -8.782mA
-559mV    -3.266mA   -3.933mA   -3.841mA
-496mV    -1.438mA   -2.052mA   -1.583mA
-412mV    -512.3uA   -729.3uA   -564.2uA
-286mV    -286.6uA   -261.9uA   -348.8uA
1V        -79.89nA   0A         -21.82uA
[POWER_clamp]
|Voltage   I(typ)   I(min)   I(max)
-995mV    32.01mA    50.49mA    25.97mA
-974mV    26.3mA     42.33mA    22.63mA
-953mV    21.89mA    35.2mA     20.31mA
-932mV    18.6mA     29.12mA    18.65mA
-911mV    16.18mA    24.08mA    17.37mA
-869mV    13.01mA    16.74mA    15.37mA
-827mV    10.99mA    12.19mA    13.65mA
-785mV    9.438mA    9.371mA    12.02mA
-680mV    6.228mA    5.537mA    8.194mA
-491mV    1.877mA    1.844mA    2.561mA
-344mV    370.5uA    455uA      446.7uA
1V        0A         0A         35.82uA
[Ramp]
| variable   typ   min   max
dV/dt_r   0.381/0.127n   0.364/0.153n   0.391/0.110n
dV/dt_f   0.383/0.110n   0.374/0.140n   0.387/93.606p
R_load = 50.000
[Rising Waveform]
R_fixture= 50.000
V_fixture= 0.0
V_fixture_min= 0.0
V_fixture_max= 0.0
|time   V(typ)   V(min)   V(max)
0s        819.6nV    4.422uV    379.7nV
366ps     64.49uV    36.33uV    2.851mV
415ps     -589.6uV   68.71uV    88.76mV
477ps     7.551mV    -420.8uV   330.8mV
572ps     231.1mV    7.176mV    584.7mV
663ps     499mV      156.5mV    638mV
738ps     593.2mV    355.4mV    647.5mV
868ps     627mV      557mV      651.4mV
1.128ns   633.7mV    603.2mV    652.3mV
10ns      634.3mV    606.9mV    652.4mV
[Rising Waveform]
R_fixture= 50.000
V_fixture= 1.000
V_fixture_min= 0.970
V_fixture_max= 1.030
|time   V(typ)   V(min)   V(max)
0s        361mV      347.1mV    385.4mV
378ps     360.9mV    347.1mV    391.6mV
418ps     360.5mV    347.1mV    466.4mV
486ps     371mV      346.6mV    770.1mV
543ps     503.9mV    347.5mV    936mV
613ps     776.6mV    390.4mV    1.008V
711ps     963mV      678.2mV    1.026V
835ps     995.4mV    925mV      1.029V
1.039ns   999.4mV    967.6mV    1.03V
10ns      1V         970mV      1.03V
[Falling Waveform]
R_fixture= 50.000
V_fixture= 1.000
V_fixture_min= 0.970
V_fixture_max= 1.030
|time   V(typ)   V(min)   V(max)
0s        1V         970mV      1.03V
379ps     999.9mV    970mV      1.03V
412ps     1.001V     970mV      954mV
487ps     995.4mV    971.3mV    619.9mV
536ps     890.2mV    974mV      474.4mV
608ps     620.2mV    942.4mV    408.9mV
711ps     405.8mV    697.5mV    391mV
841ps     369.5mV    414.6mV    387.1mV
1.101ns   362.3mV    353.8mV    385.8mV
10ns      361mV      347.1mV    385.4mV
[Falling Waveform]
R_fixture= 50.000
V_fixture= 0.0
V_fixture_min= 0.0
V_fixture_max= 0.0
|time   V(typ)   V(min)   V(max)
0s        634.3mV    606.8mV    652.4mV
377ps     634.7mV    606.9mV    651.2mV
415ps     636.8mV    607.2mV    552.8mV
480ps     627.9mV    608.9mV    244.1mV
530ps     509.9mV    609.9mV    85.49mV
594ps     247.6mV    575.6mV    21.97mV
691ps     41.42mV    308.2mV    4.595mV
801ps     6.077mV    60.31mV    1.225mV
991ps     943.2uV    3.716mV    188.8uV
10ns      829nV      4.434uV    387.1nV
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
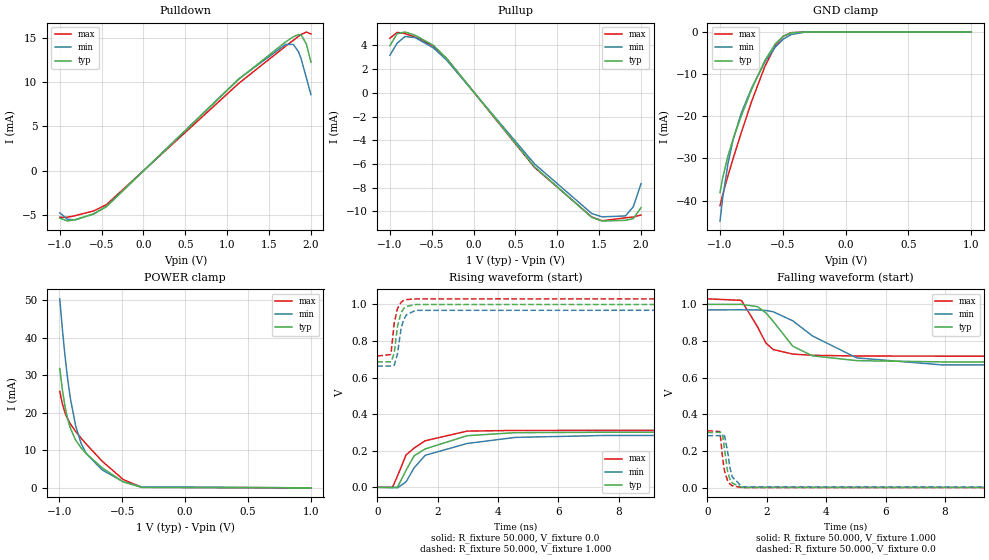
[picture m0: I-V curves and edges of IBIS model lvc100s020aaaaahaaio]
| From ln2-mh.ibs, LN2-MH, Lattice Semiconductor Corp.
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|   Model lvc100s020aaaaahaaio
[Model] lvc100s020aaaaahaaio
| Clamp models do not include dynamic input termination. Please refer to
| the lvc100axxxaaaaahaain model for input termination.
Model_type I/O
Polarity   Non-Inverting
Enable   Active-Low
Vinl =  0.350V
Vinh =  0.650V
Vmeas =  0.500V
Cref =  0.0F
Rref =  1.000M
Vref =  0.0V
C_comp   2.000pF   1.500pF   2.500pF
[Temperature Range]   25.000   0.125k   -40.000
[Voltage Range]   1.000V   0.970V   1.030V
[C Comp Corner]
C_comp   2.000pF   1.500pF   2.500pF
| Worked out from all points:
|   slope of the pulldown table from 0 to 0.15 V, typ, clamps not added: 108 ohm
|   slope of the pullup table from 0 to 0.15 V, typ, clamps not added: 110 ohm
|   GND clamp passes 1 mA (typ) near -0.50 V on its own axis
|   POWER clamp passes 1 mA (typ) near -0.45 V on its own axis
|   rising waveform, R_fixture 50.000, V_fixture 0.0: 20-80 % time 1.2ns typ, 1.6ns min, 864ps max; typ from 0 V to 0.301 V
|   rising waveform, R_fixture 50.000, V_fixture 1.000: 20-80 % time 174ps typ, 193ps min, 162ps max; typ from 0.686 V to 1 V
|   falling waveform, R_fixture 50.000, V_fixture 1.000: 20-80 % time 1.01ns typ, 1.76ns min, 593ps max; typ from 1 V to 0.686 V
|   falling waveform, R_fixture 50.000, V_fixture 0.0: 20-80 % time 171ps typ, 184ps min, 162ps max; typ from 0.301 V to 0 V
[Pulldown]
|Voltage   I(typ)   I(min)   I(max)
-1V       -5.336mA   -4.741mA   -5.244mA
-907mV    -5.666mA   -5.481mA   -5.236mA
-814mV    -5.51mA    -5.524mA   -5.056mA
-597mV    -4.881mA   -4.876mA   -4.537mA
-442mV    -4.029mA   -4.023mA   -3.816mA
1.139V    10.34mA    10.38mA    9.878mA
1.697V    14.54mA    14.26mA    14.06mA
1.79V     15.13mA    14.26mA    14.73mA
1.852V    15.37mA    13.43mA    15.18mA
1.883V    15.32mA    12.63mA    15.39mA
1.945V    14.33mA    10.51mA    15.66mA
2V        12.26mA    8.583mA    15.44mA
[Pullup]
|Voltage   I(typ)   I(min)   I(max)
-1V       3.975mA    3.174mA    4.603mA
-914mV    4.986mA    4.176mA    5.1mA
-821mV    5.129mA    4.75mA     4.999mA
-697mV    4.858mA    4.657mA    4.708mA
-480mV    3.999mA    3.792mA    3.924mA
-325mV    2.926mA    2.782mA    2.918mA
729mV     -6.25mA    -6.002mA   -6.3mA
1.411V    -10.5mA    -10.18mA   -10.47mA
1.535V    -10.81mA   -10.46mA   -10.79mA
1.814V    -10.75mA   -10.38mA   -10.54mA
1.907V    -10.61mA   -9.611mA   -10.47mA
2V        -9.681mA   -7.652mA   -10.3mA
[GND_clamp]
|Voltage   I(typ)   I(min)   I(max)
-1V       -38.12mA   -44.85mA   -41.21mA
-979mV    -34.68mA   -39.51mA   -38.64mA
-937mV    -29.43mA   -31.27mA   -34.13mA
-895mV    -25.33mA   -25.48mA   -29.97mA
-832mV    -20.01mA   -19.35mA   -24mA
-748mV    -13.6mA    -13.25mA   -16.46mA
-643mV    -6.759mA   -7.17mA    -8.178mA
-559mV    -2.781mA   -3.541mA   -3.248mA
-496mV    -972.8uA   -1.676mA   -1.012mA
-433mV    -198uA     -594.9uA   -143.9uA
-328mV    -6.321uA   -55.61uA   -1.827uA
1V        42.38pA    0A         0A
[POWER_clamp]
|Voltage   I(typ)   I(min)   I(max)
-995mV    31.81mA    50.36mA    25.7mA
-974mV    26.08mA    42.19mA    22.34mA
-953mV    21.65mA    35.04mA    20mA
-932mV    18.35mA    28.96mA    18.33mA
-911mV    15.92mA    23.9mA     17.05mA
-869mV    12.73mA    16.55mA    15.04mA
-827mV    10.71mA    11.99mA    13.31mA
-785mV    9.149mA    9.156mA    11.68mA
-659mV    5.357mA    4.783mA    7.128mA
-491mV    1.591mA    1.628mA    2.217mA
-344mV    125.7uA    266.7uA    146.2uA
1V        0A         0A         0A
[Ramp]
| variable   typ   min   max
dV/dt_r   0.181/1.201n   0.171/1.602n   0.187/0.865n
dV/dt_f   0.189/1.021n   0.184/1.758n   0.187/0.599n
R_load = 50.000
[Rising Waveform]
R_fixture= 50.000
V_fixture= 0.0
V_fixture_min= 0.0
V_fixture_max= 0.0
|time   V(typ)   V(min)   V(max)
0s        1.752uV    9.314uV    796.4nV
503ps     -1.97mV    -206uV     -106.4uV
671ps     1.286mV    -2.898mV   62.96mV
955ps     93.83mV    30.61mV    177.6mV
1.221ns   172.5mV    106.6mV    214.4mV
1.588ns   209.8mV    175.1mV    254.6mV
2.976ns   282.1mV    239.5mV    307.2mV
4.581ns   298.7mV    272.9mV    310.9mV
7.538ns   301.1mV    283.3mV    311.2mV
50ns      301.2mV    284.3mV    311.2mV
[Rising Waveform]
R_fixture= 50.000
V_fixture= 1.000
V_fixture_min= 0.970
V_fixture_max= 1.030
|time   V(typ)   V(min)   V(max)
0s        685.7mV    662.8mV    717.8mV
434ps     685.7mV    663mV      725.3mV
466ps     687.9mV    662.9mV    747.7mV
560ps     734.4mV    666.9mV    897.7mV
667ps     878.9mV    728.6mV    976.7mV
787ps     954.1mV    866.1mV    1.011V
867ps     975.7mV    914.1mV    1.021V
957ps     988mV      941.7mV    1.026V
1.267ns   999.1mV    967.3mV    1.03V
50ns      1V         970mV      1.03V
[Falling Waveform]
R_fixture= 50.000
V_fixture= 1.000
V_fixture_min= 0.970
V_fixture_max= 1.030
|time   V(typ)   V(min)   V(max)
0s        1V         970mV      1.03V
1.143ns   1V         970.4mV    1.022V
1.683ns   987.8mV    969.7mV    878.5mV
1.963ns   954.6mV    966.9mV    790.4mV
2.213ns   907.9mV    959.8mV    753.7mV
2.872ns   772.1mV    910.6mV    729.2mV
3.533ns   719.7mV    828.3mV    722.5mV
5.023ns   693.3mV    708.4mV    718.6mV
7.893ns   686.5mV    670.2mV    717.8mV
50ns      685.7mV    662.8mV    717.8mV
[Falling Waveform]
R_fixture= 50.000
V_fixture= 0.0
V_fixture_min= 0.0
V_fixture_max= 0.0
|time   V(typ)   V(min)   V(max)
0s        301.2mV    284.3mV    311.2mV
407ps     302.7mV    284.5mV    307.1mV
440ps     303mV      285mV      278.3mV
510ps     291.2mV    286.6mV    161.7mV
580ps     203.9mV    283mV      87.74mV
683ps     85.98mV    193.4mV    37.24mV
753ps     48.74mV    113.6mV    21.23mV
833ps     26.03mV    60.01mV    11.42mV
1.163ns   2.623mV    5.525mV    1.386mV
50ns      1.75uV     9.328uV    795.5nV
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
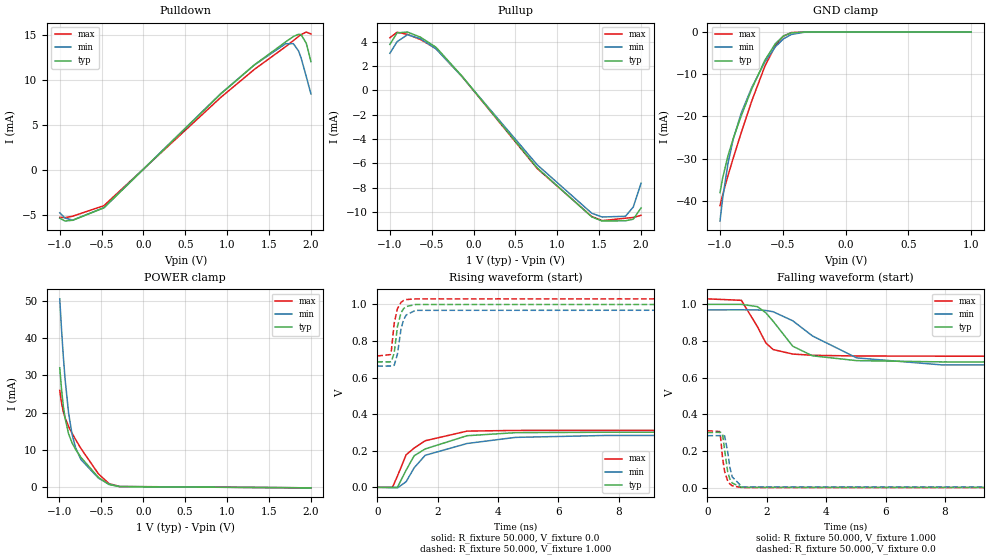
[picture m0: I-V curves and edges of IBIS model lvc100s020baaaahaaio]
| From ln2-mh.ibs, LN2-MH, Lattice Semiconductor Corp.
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|   Model lvc100s020baaaahaaio
[Model] lvc100s020baaaahaaio
| Clamp models do not include dynamic input termination. Please refer to
| the lvc100axxxbaaaahaain model for input termination.
Model_type I/O
Polarity   Non-Inverting
Enable   Active-Low
Vinl =  0.350V
Vinh =  0.650V
Vmeas =  0.500V
Cref =  0.0F
Rref =  1.000M
Vref =  0.0V
C_comp   2.000pF   1.500pF   2.500pF
[Temperature Range]   25.000   0.125k   -40.000
[Voltage Range]   1.000V   0.970V   1.030V
[C Comp Corner]
C_comp   2.000pF   1.500pF   2.500pF
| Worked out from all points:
|   slope of the pulldown table from 0 to 0.15 V, typ, clamps not added: 108 ohm
|   slope of the pullup table from 0 to 0.15 V, typ, clamps not added: 116 ohm
|   GND clamp passes 1 mA (typ) near -0.50 V on its own axis
|   POWER clamp passes 1 mA (typ) near -0.43 V on its own axis
|   rising waveform, R_fixture 50.000, V_fixture 0.0: 20-80 % time 1.2ns typ, 1.6ns min, 864ps max; typ from 0 V to 0.301 V
|   rising waveform, R_fixture 50.000, V_fixture 1.000: 20-80 % time 174ps typ, 193ps min, 162ps max; typ from 0.686 V to 1 V
|   falling waveform, R_fixture 50.000, V_fixture 1.000: 20-80 % time 1.01ns typ, 1.76ns min, 593ps max; typ from 1 V to 0.686 V
|   falling waveform, R_fixture 50.000, V_fixture 0.0: 20-80 % time 171ps typ, 184ps min, 162ps max; typ from 0.301 V to 0 V
[Pulldown]
|Voltage   I(typ)   I(min)   I(max)
-1V       -5.316mA   -4.722mA   -5.222mA
-938mV    -5.631mA   -5.305mA   -5.256mA
-845mV    -5.55mA    -5.528mA   -5.094mA
-473mV    -4.167mA   -4.157mA   -3.932mA
922mV     8.462mA    8.504mA    8.079mA
1.325V    11.7mA     11.69mA    11.2mA
1.697V    14.24mA    14.04mA    13.71mA
1.79V     14.84mA    14.05mA    14.39mA
1.852V    15.09mA    13.24mA    14.85mA
1.883V    15.05mA    12.45mA    15.06mA
1.945V    14.08mA    10.37mA    15.34mA
2V        12.06mA    8.471mA    15.13mA
[Pullup]
|Voltage   I(typ)   I(min)   I(max)
-1V       3.776mA    3.047mA    4.329mA
-914mV    4.723mA    4.002mA    4.777mA
-790mV    4.794mA    4.573mA    4.597mA
-635mV    4.372mA    4.247mA    4.181mA
-449mV    3.543mA    3.408mA    3.426mA
-139mV    1.17mA     1.138mA    1.145mA
760mV     -6.375mA   -6.122mA   -6.428mA
1.411V    -10.4mA    -10.1mA    -10.37mA
1.535V    -10.74mA   -10.41mA   -10.71mA
1.814V    -10.72mA   -10.35mA   -10.51mA
1.907V    -10.59mA   -9.587mA   -10.45mA
2V        -9.661mA   -7.634mA   -10.27mA
[GND_clamp]
|Voltage   I(typ)   I(min)   I(max)
-1V       -38.04mA   -44.76mA   -41.12mA
-979mV    -34.6mA    -39.43mA   -38.56mA
-937mV    -29.35mA   -31.19mA   -34.05mA
-895mV    -25.25mA   -25.4mA    -29.89mA
-832mV    -19.93mA   -19.28mA   -23.93mA
-748mV    -13.53mA   -13.18mA   -16.39mA
-643mV    -6.699mA   -7.109mA   -8.115mA
-559mV    -2.738mA   -3.494mA   -3.203mA
-496mV    -950.2uA   -1.644mA   -989.9uA
-433mV    -191.8uA   -578.6uA   -139.6uA
-328mV    -5.96uA    -52.93uA   -1.703uA
1V        0A         0A         0A
[POWER_clamp]
|Voltage   I(typ)   I(min)   I(max)
-995mV    32.01mA    50.49mA    25.97mA
-974mV    26.3mA     42.33mA    22.63mA
-953mV    21.89mA    35.2mA     20.31mA
-932mV    18.6mA     29.12mA    18.65mA
-890mV    14.38mA    19.99mA    16.32mA
-848mV    11.92mA    14.19mA    14.49mA
-806mV    10.18mA    10.62mA    12.83mA
-743mV    8.079mA    7.495mA    10.45mA
-533mV    2.652mA    2.481mA    3.608mA
-407mV    775.9uA    886.3uA    1.02mA
-281mV    222uA      236.7uA    263uA
2V        -103.7uA   -104.4uA   -104.8uA
[Ramp]
| variable   typ   min   max
dV/dt_r   0.181/1.201n   0.171/1.602n   0.187/0.865n
dV/dt_f   0.189/1.021n   0.184/1.758n   0.187/0.599n
R_load = 50.000
[Rising Waveform]
R_fixture= 50.000
V_fixture= 0.0
V_fixture_min= 0.0
V_fixture_max= 0.0
|time   V(typ)   V(min)   V(max)
0s        1.752uV    9.314uV    796.4nV
503ps     -1.97mV    -206uV     -106.4uV
671ps     1.286mV    -2.898mV   62.96mV
955ps     93.83mV    30.61mV    177.6mV
1.221ns   172.5mV    106.6mV    214.4mV
1.588ns   209.8mV    175.1mV    254.6mV
2.976ns   282.1mV    239.5mV    307.2mV
4.581ns   298.7mV    272.9mV    310.9mV
7.538ns   301.1mV    283.3mV    311.2mV
50ns      301.2mV    284.3mV    311.2mV
[Rising Waveform]
R_fixture= 50.000
V_fixture= 1.000
V_fixture_min= 0.970
V_fixture_max= 1.030
|time   V(typ)   V(min)   V(max)
0s        685.7mV    662.8mV    717.8mV
434ps     685.7mV    663mV      725.3mV
466ps     687.9mV    662.9mV    747.7mV
560ps     734.4mV    666.9mV    897.7mV
667ps     878.9mV    728.6mV    976.7mV
787ps     954.1mV    866.1mV    1.011V
867ps     975.7mV    914.1mV    1.021V
957ps     988mV      941.7mV    1.026V
1.267ns   999.1mV    967.3mV    1.03V
50ns      1V         970mV      1.03V
[Falling Waveform]
R_fixture= 50.000
V_fixture= 1.000
V_fixture_min= 0.970
V_fixture_max= 1.030
|time   V(typ)   V(min)   V(max)
0s        1V         970mV      1.03V
1.143ns   1V         970.4mV    1.022V
1.683ns   987.8mV    969.7mV    878.5mV
1.963ns   954.6mV    966.9mV    790.4mV
2.213ns   907.9mV    959.8mV    753.7mV
2.872ns   772.1mV    910.6mV    729.2mV
3.533ns   719.7mV    828.3mV    722.5mV
5.023ns   693.3mV    708.4mV    718.6mV
7.893ns   686.5mV    670.2mV    717.8mV
50ns      685.7mV    662.8mV    717.8mV
[Falling Waveform]
R_fixture= 50.000
V_fixture= 0.0
V_fixture_min= 0.0
V_fixture_max= 0.0
|time   V(typ)   V(min)   V(max)
0s        301.2mV    284.3mV    311.2mV
407ps     302.7mV    284.5mV    307.1mV
440ps     303mV      285mV      278.3mV
510ps     291.2mV    286.6mV    161.7mV
580ps     203.9mV    283mV      87.74mV
683ps     85.98mV    193.4mV    37.24mV
753ps     48.74mV    113.6mV    21.23mV
833ps     26.03mV    60.01mV    11.42mV
1.163ns   2.623mV    5.525mV    1.386mV
50ns      1.75uV     9.328uV    795.5nV
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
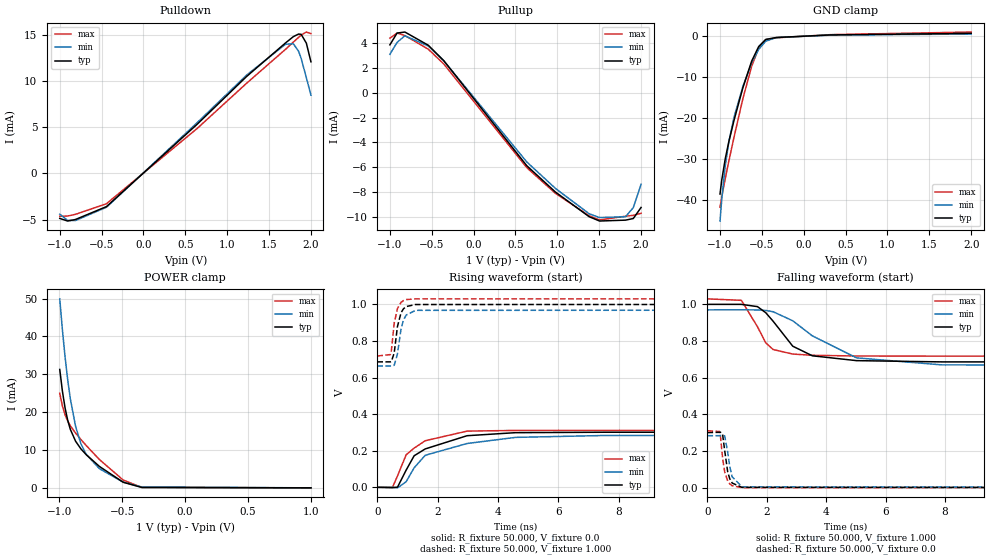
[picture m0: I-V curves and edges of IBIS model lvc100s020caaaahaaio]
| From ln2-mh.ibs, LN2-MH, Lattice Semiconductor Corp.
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|   Model lvc100s020caaaahaaio
[Model] lvc100s020caaaahaaio
| Clamp models do not include dynamic input termination. Please refer to
| the lvc100axxxcaaaahaain model for input termination.
Model_type I/O
Polarity   Non-Inverting
Enable   Active-Low
Vinl =  0.350V
Vinh =  0.650V
Vmeas =  0.500V
Cref =  0.0F
Rref =  1.000M
Vref =  0.0V
C_comp   2.000pF   1.500pF   2.500pF
[Temperature Range]   25.000   0.125k   -40.000
[Voltage Range]   1.000V   0.970V   1.030V
[C Comp Corner]
C_comp   2.000pF   1.500pF   2.500pF
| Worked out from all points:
|   slope of the pulldown table from 0 to 0.15 V, typ, clamps not added: 121 ohm
|   slope of the pullup table from 0 to 0.15 V, typ, clamps not added: 111 ohm
|   GND clamp passes 1 mA (typ) near -0.47 V on its own axis
|   POWER clamp passes 1 mA (typ) near -0.46 V on its own axis
|   rising waveform, R_fixture 50.000, V_fixture 0.0: 20-80 % time 1.2ns typ, 1.6ns min, 864ps max; typ from 0 V to 0.301 V
|   rising waveform, R_fixture 50.000, V_fixture 1.000: 20-80 % time 174ps typ, 193ps min, 162ps max; typ from 0.686 V to 1 V
|   falling waveform, R_fixture 50.000, V_fixture 1.000: 20-80 % time 1.01ns typ, 1.76ns min, 593ps max; typ from 1 V to 0.686 V
|   falling waveform, R_fixture 50.000, V_fixture 0.0: 20-80 % time 171ps typ, 184ps min, 162ps max; typ from 0.301 V to 0 V
[Pulldown]
|Voltage   I(typ)   I(min)   I(max)
-1V       -4.878mA   -4.415mA   -4.647mA
-907mV    -5.161mA   -5.09mA    -4.621mA
-814mV    -5.001mA   -5.115mA   -4.442mA
-442mV    -3.596mA   -3.668mA   -3.283mA
643mV     5.359mA    5.53mA     4.899mA
1.232V    10.53mA    10.68mA    9.795mA
1.697V    14.17mA    14.03mA    13.48mA
1.79V     14.85mA    14.07mA    14.26mA
1.852V    15.13mA    13.27mA    14.77mA
1.883V    15.1mA     12.49mA    15.02mA
1.945V    14.15mA    10.4mA     15.35mA
2V        12.12mA    8.501mA    15.18mA
[Pullup]
|Voltage   I(typ)   I(min)   I(max)
-1V       3.84mA     3.08mA     4.377mA
-914mV    4.787mA    4.038mA    4.788mA
-821mV    4.869mA    4.565mA    4.59mA
-542mV    3.81mA     3.745mA    3.492mA
-356mV    2.566mA    2.556mA    2.302mA
636mV     -5.877mA   -5.572mA   -6.029mA
977mV     -7.981mA   -7.689mA   -8.084mA
1.38V     -9.965mA   -9.729mA   -9.889mA
1.504V    -10.31mA   -10.03mA   -10.22mA
1.814V    -10.24mA   -9.969mA   -9.923mA
1.907V    -10.11mA   -9.235mA   -9.856mA
2V        -9.222mA   -7.354mA   -9.687mA
[GND_clamp]
|Voltage   I(typ)   I(min)   I(max)
-1V       -38.58mA   -45.18mA   -41.8mA
-979mV    -35.16mA   -39.86mA   -39.25mA
-937mV    -29.93mA   -31.65mA   -34.75mA
-895mV    -25.83mA   -25.87mA   -30.59mA
-832mV    -20.52mA   -19.76mA   -24.62mA
-727mV    -12.62mA   -12.32mA   -15.28mA
-622mV    -6.113mA   -6.552mA   -7.373mA
-538mV    -2.537mA   -3.22mA    -2.933mA
-454mV    -801.3uA   -1.232mA   -848.9uA
-328mV    -333.7uA   -332.7uA   -402.2uA
323mV     301.4uA    251.4uA    374.9uA
2V        684.6uA    526.6uA    1.009mA
[POWER_clamp]
|Voltage   I(typ)   I(min)   I(max)
-995mV    31.28mA    49.94mA    24.97mA
-974mV    25.56mA    41.77mA    21.63mA
-953mV    21.15mA    34.64mA    19.32mA
-932mV    17.87mA    28.56mA    17.67mA
-911mV    15.45mA    23.52mA    16.41mA
-869mV    12.3mA     16.19mA    14.45mA
-827mV    10.3mA     11.65mA    12.77mA
-785mV    8.774mA    8.843mA    11.19mA
-680mV    5.655mA    5.063mA    7.48mA
-491mV    1.477mA    1.511mA    2.059mA
-344mV    103.3uA    232.5uA    114.2uA
1V        0A         0A         0A
[Ramp]
| variable   typ   min   max
dV/dt_r   0.181/1.201n   0.171/1.602n   0.187/0.865n
dV/dt_f   0.189/1.021n   0.184/1.758n   0.187/0.599n
R_load = 50.000
[Rising Waveform]
R_fixture= 50.000
V_fixture= 0.0
V_fixture_min= 0.0
V_fixture_max= 0.0
|time   V(typ)   V(min)   V(max)
0s        1.752uV    9.314uV    796.4nV
503ps     -1.97mV    -206uV     -106.4uV
671ps     1.286mV    -2.898mV   62.96mV
955ps     93.83mV    30.61mV    177.6mV
1.221ns   172.5mV    106.6mV    214.4mV
1.588ns   209.8mV    175.1mV    254.6mV
2.976ns   282.1mV    239.5mV    307.2mV
4.581ns   298.7mV    272.9mV    310.9mV
7.538ns   301.1mV    283.3mV    311.2mV
50ns      301.2mV    284.3mV    311.2mV
[Rising Waveform]
R_fixture= 50.000
V_fixture= 1.000
V_fixture_min= 0.970
V_fixture_max= 1.030
|time   V(typ)   V(min)   V(max)
0s        685.7mV    662.8mV    717.8mV
434ps     685.7mV    663mV      725.3mV
466ps     687.9mV    662.9mV    747.7mV
560ps     734.4mV    666.9mV    897.7mV
667ps     878.9mV    728.6mV    976.7mV
787ps     954.1mV    866.1mV    1.011V
867ps     975.7mV    914.1mV    1.021V
957ps     988mV      941.7mV    1.026V
1.267ns   999.1mV    967.3mV    1.03V
50ns      1V         970mV      1.03V
[Falling Waveform]
R_fixture= 50.000
V_fixture= 1.000
V_fixture_min= 0.970
V_fixture_max= 1.030
|time   V(typ)   V(min)   V(max)
0s        1V         970mV      1.03V
1.143ns   1V         970.4mV    1.022V
1.683ns   987.8mV    969.7mV    878.5mV
1.963ns   954.6mV    966.9mV    790.4mV
2.213ns   907.9mV    959.8mV    753.7mV
2.872ns   772.1mV    910.6mV    729.2mV
3.533ns   719.7mV    828.3mV    722.5mV
5.023ns   693.3mV    708.4mV    718.6mV
7.893ns   686.5mV    670.2mV    717.8mV
50ns      685.7mV    662.8mV    717.8mV
[Falling Waveform]
R_fixture= 50.000
V_fixture= 0.0
V_fixture_min= 0.0
V_fixture_max= 0.0
|time   V(typ)   V(min)   V(max)
0s        301.2mV    284.3mV    311.2mV
407ps     302.7mV    284.5mV    307.1mV
440ps     303mV      285mV      278.3mV
510ps     291.2mV    286.6mV    161.7mV
580ps     203.9mV    283mV      87.74mV
683ps     85.98mV    193.4mV    37.24mV
753ps     48.74mV    113.6mV    21.23mV
833ps     26.03mV    60.01mV    11.42mV
1.163ns   2.623mV    5.525mV    1.386mV
50ns      1.75uV     9.328uV    795.5nV
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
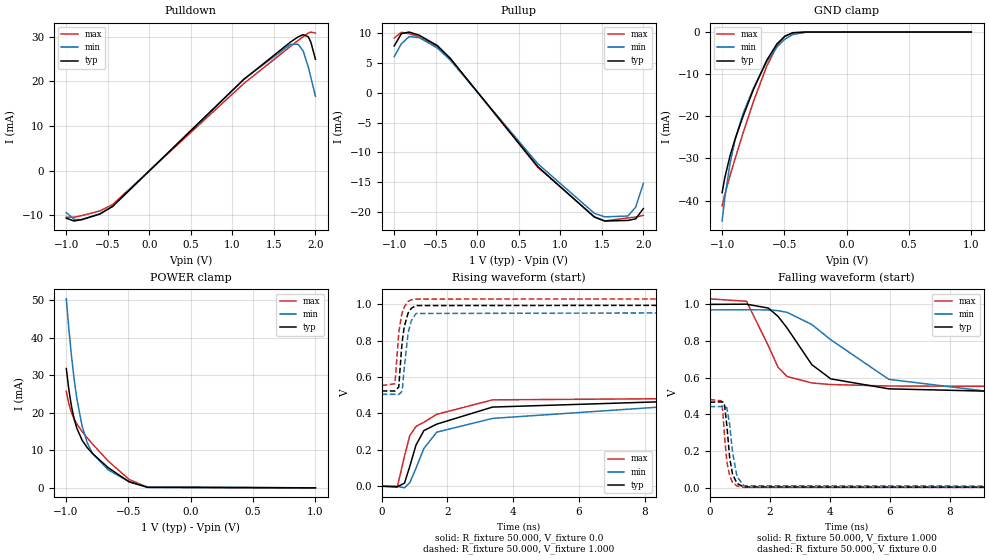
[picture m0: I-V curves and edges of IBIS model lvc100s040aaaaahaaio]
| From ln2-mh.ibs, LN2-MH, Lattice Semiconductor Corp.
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|   Model lvc100s040aaaaahaaio
[Model] lvc100s040aaaaahaaio
| Clamp models do not include dynamic input termination. Please refer to
| the lvc100axxxaaaaahaain model for input termination.
Model_type I/O
Polarity   Non-Inverting
Enable   Active-Low
Vinl =  0.350V
Vinh =  0.650V
Vmeas =  0.500V
Cref =  0.0F
Rref =  1.000M
Vref =  0.0V
C_comp   2.000pF   1.500pF   2.500pF
[Temperature Range]   25.000   0.125k   -40.000
[Voltage Range]   1.000V   0.970V   1.030V
[C Comp Corner]
C_comp   2.000pF   1.500pF   2.500pF
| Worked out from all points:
|   slope of the pulldown table from 0 to 0.15 V, typ, clamps not added: 54.8 ohm
|   slope of the pullup table from 0 to 0.15 V, typ, clamps not added: 55.6 ohm
|   GND clamp passes 1 mA (typ) near -0.50 V on its own axis
|   POWER clamp passes 1 mA (typ) near -0.45 V on its own axis
|   rising waveform, R_fixture 50.000, V_fixture 0.0: 20-80 % time 1.4ns typ, 1.88ns min, 971ps max; typ from 0 V to 0.467 V
|   rising waveform, R_fixture 50.000, V_fixture 1.000: 20-80 % time 166ps typ, 182ps min, 158ps max; typ from 0.524 V to 1 V
|   falling waveform, R_fixture 50.000, V_fixture 1.000: 20-80 % time 1.32ns typ, 2.33ns min, 757ps max; typ from 1 V to 0.524 V
|   falling waveform, R_fixture 50.000, V_fixture 0.0: 20-80 % time 180ps typ, 202ps min, 166ps max; typ from 0.467 V to 0 V
[Pulldown]
|Voltage   I(typ)   I(min)   I(max)
-1V       -10.61mA   -9.357mA   -10.43mA
-907mV    -11.25mA   -10.87mA   -10.39mA
-814mV    -10.93mA   -10.96mA   -10.04mA
-597mV    -9.684mA   -9.668mA   -9.009mA
-442mV    -7.977mA   -7.964mA   -7.56mA
1.139V    20.47mA    20.54mA    19.56mA
1.697V    28.78mA    28.27mA    27.81mA
1.79V     29.96mA    28.35mA    29.15mA
1.852V    30.49mA    26.82mA    30.03mA
1.914V    29.99mA    23.22mA    30.83mA
1.945V    28.78mA    20.88mA    31.06mA
2V        24.95mA    16.69mA    30.83mA
[Pullup]
|Voltage   I(typ)   I(min)   I(max)
-1V       7.88mA     6.096mA    9.215mA
-914mV    9.941mA    8.247mA    10.17mA
-821mV    10.22mA    9.449mA    9.957mA
-697mV    9.669mA    9.265mA    9.372mA
-480mV    7.939mA    7.528mA    7.795mA
-325mV    5.794mA    5.511mA    5.78mA
729mV     -12.39mA   -11.9mA    -12.49mA
1.411V    -20.87mA   -20.24mA   -20.82mA
1.535V    -21.52mA   -20.82mA   -21.51mA
1.814V    -21.42mA   -20.68mA   -21mA
1.907V    -21.16mA   -19.2mA    -20.87mA
2V        -19.43mA   -15.22mA   -20.55mA
[GND_clamp]
|Voltage   I(typ)   I(min)   I(max)
-1V       -38.12mA   -44.85mA   -41.21mA
-979mV    -34.68mA   -39.51mA   -38.64mA
-937mV    -29.43mA   -31.27mA   -34.13mA
-895mV    -25.33mA   -25.48mA   -29.97mA
-832mV    -20.01mA   -19.35mA   -24mA
-748mV    -13.6mA    -13.25mA   -16.46mA
-643mV    -6.759mA   -7.17mA    -8.178mA
-559mV    -2.781mA   -3.541mA   -3.248mA
-496mV    -972.8uA   -1.676mA   -1.012mA
-433mV    -198uA     -594.9uA   -143.9uA
-328mV    -6.321uA   -55.61uA   -1.827uA
1V        42.39pA    0A         0A
[POWER_clamp]
|Voltage   I(typ)   I(min)   I(max)
-995mV    31.81mA    50.36mA    25.7mA
-974mV    26.08mA    42.19mA    22.34mA
-953mV    21.65mA    35.04mA    20mA
-932mV    18.35mA    28.96mA    18.33mA
-911mV    15.92mA    23.9mA     17.05mA
-869mV    12.73mA    16.55mA    15.04mA
-827mV    10.71mA    11.99mA    13.31mA
-785mV    9.149mA    9.156mA    11.68mA
-659mV    5.357mA    4.783mA    7.128mA
-491mV    1.591mA    1.628mA    2.217mA
-344mV    125.7uA    266.7uA    146.2uA
1V        0A         0A         0A
[Ramp]
| variable   typ   min   max
dV/dt_r   0.280/1.398n   0.266/1.881n   0.289/0.971n
dV/dt_f   0.286/1.321n   0.279/2.332n   0.286/0.763n
R_load = 50.000
[Rising Waveform]
R_fixture= 50.000
V_fixture= 0.0
V_fixture_min= 0.0
V_fixture_max= 0.0
|time   V(typ)   V(min)   V(max)
0s        1.288uV    6.875uV    590.5nV
474ps     -2.686mV   -304.3uV   -4.34mV
692ps     16.94mV    -8.809mV   165.5mV
854ps     109.2mV    19.69mV    278.8mV
1.043ns   226.4mV    99.38mV    328.6mV
1.282ns   305.9mV    207.5mV    351.8mV
1.673ns   341.3mV    297mV      395.3mV
3.372ns   435.2mV    372.9mV    474.8mV
8.852ns   466.5mV    440.1mV    481.5mV
50ns      466.8mV    442.7mV    481.5mV
[Rising Waveform]
R_fixture= 50.000
V_fixture= 1.000
V_fixture_min= 0.970
V_fixture_max= 1.030
|time   V(typ)   V(min)   V(max)
0s        523.9mV    505.3mV    553.2mV
402ps     523.5mV    505.3mV    563.4mV
518ps     545.6mV    505.2mV    842.7mV
600ps     749mV      517.6mV    937.7mV
636ps     814.8mV    548.3mV    961.9mV
685ps     876.7mV    650.2mV    985.4mV
803ps     952.5mV    842.3mV    1.016V
902ps     978.3mV    910.7mV    1.025V
1.043ns   993.2mV    949.6mV    1.029V
50ns      1V         970mV      1.03V
[Falling Waveform]
R_fixture= 50.000
V_fixture= 1.000
V_fixture_min= 0.970
V_fixture_max= 1.030
|time   V(typ)   V(min)   V(max)
0s        1V         970mV      1.03V
1.228ns   1.001V     970.7mV    1.017V
1.956ns   979.9mV    969.5mV    774.2mV
2.278ns   934.7mV    965.8mV    657.8mV
2.577ns   872.1mV    956.7mV    607.3mV
3.407ns   671.1mV    890.1mV    571.6mV
4.037ns   594mV      807.1mV    563.1mV
5.972ns   539.6mV    591.4mV    555mV
9.493ns   526mV      521.5mV    553.3mV
50ns      523.9mV    505.2mV    553.2mV
[Falling Waveform]
R_fixture= 50.000
V_fixture= 0.0
V_fixture_min= 0.0
V_fixture_max= 0.0
|time   V(typ)   V(min)   V(max)
0s        466.7mV    442.7mV    481.5mV
389ps     468.5mV    443mV      474.6mV
439ps     468.4mV    444.1mV    414.5mV
494ps     453.3mV    445.6mV    284.8mV
573ps     339.9mV    436.1mV    142.2mV
667ps     164mV      344.3mV    64.69mV
763ps     74.78mV    193.3mV    29.98mV
912ps     23.69mV    60.48mV    9.815mV
1.142ns   4.825mV    11.53mV    2.631mV
50ns      1.288uV    6.885uV    590nV
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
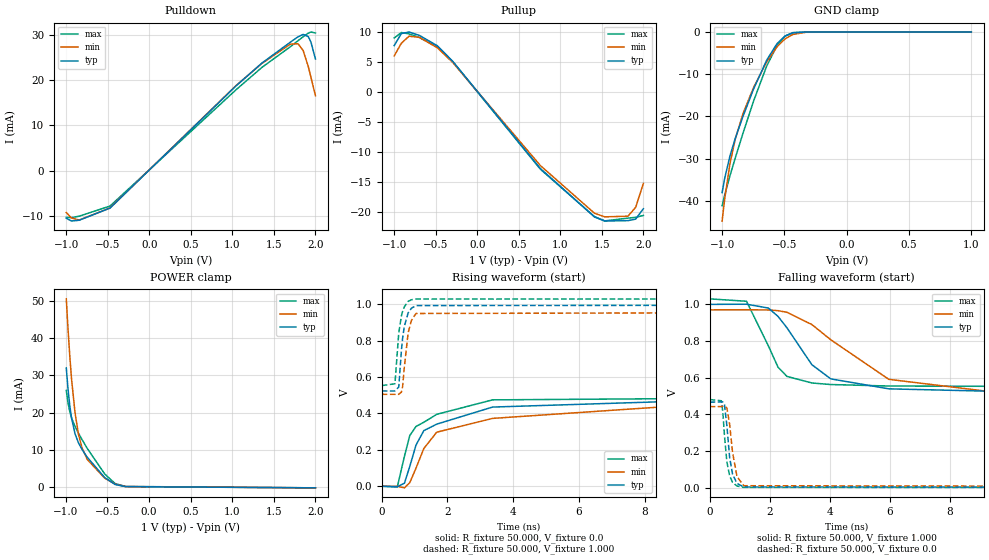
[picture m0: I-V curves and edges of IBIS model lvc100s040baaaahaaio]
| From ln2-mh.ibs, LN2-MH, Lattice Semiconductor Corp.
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|   Model lvc100s040baaaahaaio
[Model] lvc100s040baaaahaaio
| Clamp models do not include dynamic input termination. Please refer to
| the lvc100axxxbaaaahaain model for input termination.
Model_type I/O
Polarity   Non-Inverting
Enable   Active-Low
Vinl =  0.350V
Vinh =  0.650V
Vmeas =  0.500V
Cref =  0.0F
Rref =  1.000M
Vref =  0.0V
C_comp   2.000pF   1.500pF   2.500pF
[Temperature Range]   25.000   0.125k   -40.000
[Voltage Range]   1.000V   0.970V   1.030V
[C Comp Corner]
C_comp   2.000pF   1.500pF   2.500pF
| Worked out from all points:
|   slope of the pulldown table from 0 to 0.15 V, typ, clamps not added: 54.8 ohm
|   slope of the pullup table from 0 to 0.15 V, typ, clamps not added: 57.2 ohm
|   GND clamp passes 1 mA (typ) near -0.50 V on its own axis
|   POWER clamp passes 1 mA (typ) near -0.43 V on its own axis
|   rising waveform, R_fixture 50.000, V_fixture 0.0: 20-80 % time 1.4ns typ, 1.88ns min, 971ps max; typ from 0 V to 0.467 V
|   rising waveform, R_fixture 50.000, V_fixture 1.000: 20-80 % time 166ps typ, 182ps min, 158ps max; typ from 0.524 V to 1 V
|   falling waveform, R_fixture 50.000, V_fixture 1.000: 20-80 % time 1.32ns typ, 2.33ns min, 757ps max; typ from 1 V to 0.524 V
|   falling waveform, R_fixture 50.000, V_fixture 0.0: 20-80 % time 180ps typ, 202ps min, 166ps max; typ from 0.467 V to 0 V
[Pulldown]
|Voltage   I(typ)   I(min)   I(max)
-1V       -10.59mA   -9.337mA   -10.4mA
-938mV    -11.21mA   -10.54mA   -10.46mA
-845mV    -11.04mA   -10.99mA   -10.14mA
-473mV    -8.341mA   -8.309mA   -7.884mA
1.046V    18.82mA    18.9mA     17.96mA
1.356V    23.86mA    23.78mA    22.9mA
1.697V    28.48mA    28.05mA    27.47mA
1.79V     29.68mA    28.14mA    28.81mA
1.852V    30.21mA    26.63mA    29.7mA
1.914V    29.72mA    23.06mA    30.5mA
1.945V    28.54mA    20.74mA    30.74mA
2V        24.75mA    16.58mA    30.53mA
[Pullup]
|Voltage   I(typ)   I(min)   I(max)
-1V       7.682mA    5.969mA    8.941mA
-914mV    9.679mA    8.073mA    9.847mA
-821mV    9.932mA    9.24mA     9.621mA
-697mV    9.376mA    9.043mA    9.028mA
-480mV    7.654mA    7.313mA    7.453mA
-294mV    5.051mA    4.857mA    4.992mA
760mV     -12.74mA   -12.24mA   -12.85mA
1.411V    -20.77mA   -20.16mA   -20.72mA
1.535V    -21.45mA   -20.76mA   -21.43mA
1.814V    -21.39mA   -20.65mA   -20.97mA
1.907V    -21.13mA   -19.18mA   -20.84mA
2V        -19.41mA   -15.21mA   -20.53mA
[GND_clamp]
|Voltage   I(typ)   I(min)   I(max)
-1V       -38.04mA   -44.76mA   -41.12mA
-979mV    -34.6mA    -39.43mA   -38.56mA
-937mV    -29.35mA   -31.19mA   -34.05mA
-895mV    -25.25mA   -25.4mA    -29.89mA
-832mV    -19.93mA   -19.28mA   -23.93mA
-748mV    -13.53mA   -13.18mA   -16.39mA
-643mV    -6.699mA   -7.109mA   -8.115mA
-559mV    -2.738mA   -3.494mA   -3.203mA
-496mV    -950.2uA   -1.644mA   -989.9uA
-433mV    -191.7uA   -578.6uA   -139.6uA
-328mV    -5.96uA    -52.93uA   -1.703uA
1V        0A         0A         0A
[POWER_clamp]
|Voltage   I(typ)   I(min)   I(max)
-995mV    32.01mA    50.49mA    25.97mA
-974mV    26.3mA     42.33mA    22.63mA
-953mV    21.89mA    35.2mA     20.31mA
-932mV    18.6mA     29.12mA    18.65mA
-890mV    14.38mA    19.99mA    16.32mA
-848mV    11.92mA    14.19mA    14.49mA
-806mV    10.18mA    10.62mA    12.83mA
-743mV    8.079mA    7.495mA    10.45mA
-533mV    2.652mA    2.481mA    3.608mA
-407mV    775.9uA    886.3uA    1.02mA
-281mV    222uA      236.7uA    263uA
2V        -103.7uA   -104.4uA   -104.8uA
[Ramp]
| variable   typ   min   max
dV/dt_r   0.280/1.398n   0.266/1.881n   0.289/0.971n
dV/dt_f   0.286/1.321n   0.279/2.332n   0.286/0.763n
R_load = 50.000
[Rising Waveform]
R_fixture= 50.000
V_fixture= 0.0
V_fixture_min= 0.0
V_fixture_max= 0.0
|time   V(typ)   V(min)   V(max)
0s        1.288uV    6.875uV    590.5nV
474ps     -2.686mV   -304.3uV   -4.34mV
692ps     16.94mV    -8.809mV   165.5mV
854ps     109.2mV    19.69mV    278.8mV
1.043ns   226.4mV    99.38mV    328.6mV
1.282ns   305.9mV    207.5mV    351.8mV
1.673ns   341.3mV    297mV      395.3mV
3.372ns   435.2mV    372.9mV    474.8mV
8.852ns   466.5mV    440.1mV    481.5mV
50ns      466.8mV    442.7mV    481.5mV
[Rising Waveform]
R_fixture= 50.000
V_fixture= 1.000
V_fixture_min= 0.970
V_fixture_max= 1.030
|time   V(typ)   V(min)   V(max)
0s        523.9mV    505.3mV    553.2mV
402ps     523.5mV    505.3mV    563.4mV
518ps     545.6mV    505.2mV    842.7mV
600ps     749mV      517.6mV    937.7mV
636ps     814.8mV    548.3mV    961.9mV
685ps     876.7mV    650.2mV    985.4mV
803ps     952.5mV    842.3mV    1.016V
902ps     978.3mV    910.7mV    1.025V
1.043ns   993.2mV    949.6mV    1.029V
50ns      1V         970mV      1.03V
[Falling Waveform]
R_fixture= 50.000
V_fixture= 1.000
V_fixture_min= 0.970
V_fixture_max= 1.030
|time   V(typ)   V(min)   V(max)
0s        1V         970mV      1.03V
1.228ns   1.001V     970.7mV    1.017V
1.956ns   979.9mV    969.5mV    774.2mV
2.278ns   934.7mV    965.8mV    657.8mV
2.577ns   872.1mV    956.7mV    607.3mV
3.407ns   671.1mV    890.1mV    571.6mV
4.037ns   594mV      807.1mV    563.1mV
5.972ns   539.6mV    591.4mV    555mV
9.493ns   526mV      521.5mV    553.3mV
50ns      523.9mV    505.2mV    553.2mV
[Falling Waveform]
R_fixture= 50.000
V_fixture= 0.0
V_fixture_min= 0.0
V_fixture_max= 0.0
|time   V(typ)   V(min)   V(max)
0s        466.7mV    442.7mV    481.5mV
389ps     468.5mV    443mV      474.6mV
439ps     468.4mV    444.1mV    414.5mV
494ps     453.3mV    445.6mV    284.8mV
573ps     339.9mV    436.1mV    142.2mV
667ps     164mV      344.3mV    64.69mV
763ps     74.78mV    193.3mV    29.98mV
912ps     23.69mV    60.48mV    9.815mV
1.142ns   4.825mV    11.53mV    2.631mV
50ns      1.288uV    6.885uV    590nV
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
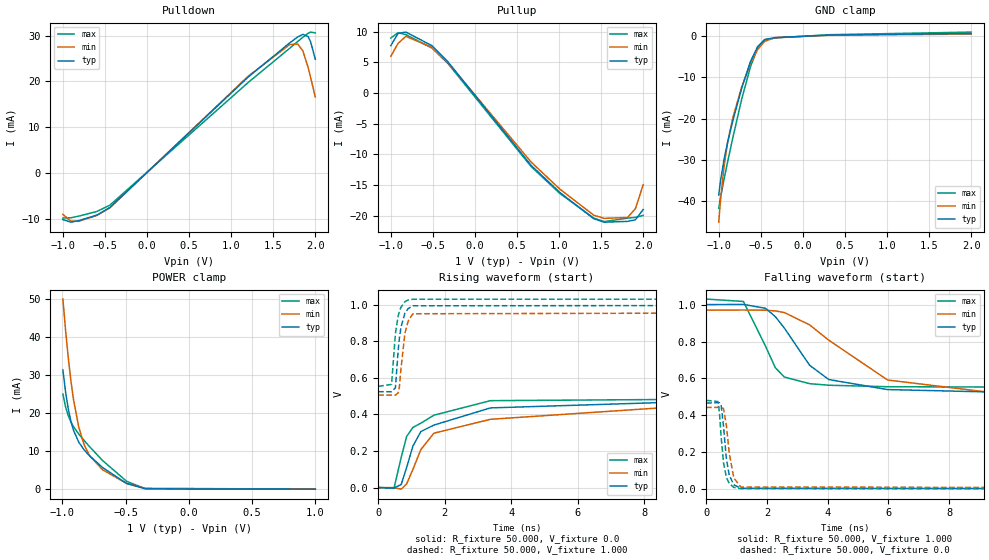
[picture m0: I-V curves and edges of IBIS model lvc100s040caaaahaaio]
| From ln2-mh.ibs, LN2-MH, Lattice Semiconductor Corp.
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|   Model lvc100s040caaaahaaio
[Model] lvc100s040caaaahaaio
| Clamp models do not include dynamic input termination. Please refer to
| the lvc100axxxcaaaahaain model for input termination.
Model_type I/O
Polarity   Non-Inverting
Enable   Active-Low
Vinl =  0.350V
Vinh =  0.650V
Vmeas =  0.500V
Cref =  0.0F
Rref =  1.000M
Vref =  0.0V
C_comp   2.000pF   1.500pF   2.500pF
[Temperature Range]   25.000   0.125k   -40.000
[Voltage Range]   1.000V   0.970V   1.030V
[C Comp Corner]
C_comp   2.000pF   1.500pF   2.500pF
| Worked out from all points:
|   slope of the pulldown table from 0 to 0.15 V, typ, clamps not added: 57.9 ohm
|   slope of the pullup table from 0 to 0.15 V, typ, clamps not added: 55.9 ohm
|   GND clamp passes 1 mA (typ) near -0.47 V on its own axis
|   POWER clamp passes 1 mA (typ) near -0.46 V on its own axis
|   rising waveform, R_fixture 50.000, V_fixture 0.0: 20-80 % time 1.4ns typ, 1.88ns min, 971ps max; typ from 0 V to 0.467 V
|   rising waveform, R_fixture 50.000, V_fixture 1.000: 20-80 % time 166ps typ, 182ps min, 158ps max; typ from 0.524 V to 1 V
|   falling waveform, R_fixture 50.000, V_fixture 1.000: 20-80 % time 1.32ns typ, 2.33ns min, 757ps max; typ from 1 V to 0.524 V
|   falling waveform, R_fixture 50.000, V_fixture 0.0: 20-80 % time 180ps typ, 202ps min, 166ps max; typ from 0.467 V to 0 V
[Pulldown]
|Voltage   I(typ)   I(min)   I(max)
-1V       -10.16mA   -9.031mA   -9.829mA
-907mV    -10.74mA   -10.48mA   -9.779mA
-814mV    -10.42mA   -10.55mA   -9.422mA
-597mV    -9.191mA   -9.269mA   -8.41mA
-442mV    -7.544mA   -7.609mA   -7.027mA
1.201V    20.92mA    21.1mA     19.73mA
1.697V    28.41mA    28.04mA    27.24mA
1.79V     29.68mA    28.16mA    28.67mA
1.852V    30.25mA    26.66mA    29.63mA
1.914V    29.79mA    23.09mA    30.49mA
1.945V    28.6mA     20.77mA    30.75mA
2V        24.82mA    16.61mA    30.57mA
[Pullup]
|Voltage   I(typ)   I(min)   I(max)
-1V       7.746mA    6.002mA    8.989mA
-914mV    9.742mA    8.109mA    9.857mA
-821mV    9.957mA    9.264mA    9.549mA
-511mV    7.742mA    7.474mA    7.347mA
-325mV    5.171mA    5.043mA    4.905mA
667mV     -11.77mA   -11.23mA   -11.96mA
1.008V    -16.18mA   -15.63mA   -16.34mA
1.411V    -20.46mA   -19.89mA   -20.36mA
1.535V    -21.04mA   -20.42mA   -20.94mA
1.814V    -20.91mA   -20.27mA   -20.38mA
1.907V    -20.65mA   -18.83mA   -20.25mA
2V        -18.97mA   -14.93mA   -19.94mA
[GND_clamp]
|Voltage   I(typ)   I(min)   I(max)
-1V       -38.58mA   -45.18mA   -41.8mA
-979mV    -35.16mA   -39.86mA   -39.25mA
-937mV    -29.93mA   -31.65mA   -34.75mA
-895mV    -25.83mA   -25.87mA   -30.59mA
-832mV    -20.52mA   -19.76mA   -24.62mA
-727mV    -12.62mA   -12.32mA   -15.28mA
-622mV    -6.113mA   -6.552mA   -7.373mA
-538mV    -2.537mA   -3.22mA    -2.933mA
-454mV    -801.3uA   -1.232mA   -848.9uA
-328mV    -333.7uA   -332.7uA   -402.2uA
323mV     301.4uA    251.4uA    374.9uA
2V        684.6uA    526.6uA    1.009mA
[POWER_clamp]
|Voltage   I(typ)   I(min)   I(max)
-995mV    31.28mA    49.94mA    24.97mA
-974mV    25.56mA    41.77mA    21.63mA
-953mV    21.15mA    34.64mA    19.32mA
-932mV    17.87mA    28.56mA    17.67mA
-911mV    15.45mA    23.52mA    16.41mA
-869mV    12.3mA     16.19mA    14.45mA
-827mV    10.3mA     11.65mA    12.77mA
-785mV    8.774mA    8.843mA    11.19mA
-680mV    5.655mA    5.063mA    7.48mA
-491mV    1.477mA    1.511mA    2.059mA
-344mV    103.3uA    232.5uA    114.2uA
1V        0A         0A         0A
[Ramp]
| variable   typ   min   max
dV/dt_r   0.280/1.398n   0.266/1.881n   0.289/0.971n
dV/dt_f   0.286/1.321n   0.279/2.332n   0.286/0.763n
R_load = 50.000
[Rising Waveform]
R_fixture= 50.000
V_fixture= 0.0
V_fixture_min= 0.0
V_fixture_max= 0.0
|time   V(typ)   V(min)   V(max)
0s        1.288uV    6.875uV    590.5nV
474ps     -2.686mV   -304.3uV   -4.34mV
692ps     16.94mV    -8.809mV   165.5mV
854ps     109.2mV    19.69mV    278.8mV
1.043ns   226.4mV    99.38mV    328.6mV
1.282ns   305.9mV    207.5mV    351.8mV
1.673ns   341.3mV    297mV      395.3mV
3.372ns   435.2mV    372.9mV    474.8mV
8.852ns   466.5mV    440.1mV    481.5mV
50ns      466.8mV    442.7mV    481.5mV
[Rising Waveform]
R_fixture= 50.000
V_fixture= 1.000
V_fixture_min= 0.970
V_fixture_max= 1.030
|time   V(typ)   V(min)   V(max)
0s        523.9mV    505.3mV    553.2mV
402ps     523.5mV    505.3mV    563.4mV
518ps     545.6mV    505.2mV    842.7mV
600ps     749mV      517.6mV    937.7mV
636ps     814.8mV    548.3mV    961.9mV
685ps     876.7mV    650.2mV    985.4mV
803ps     952.5mV    842.3mV    1.016V
902ps     978.3mV    910.7mV    1.025V
1.043ns   993.2mV    949.6mV    1.029V
50ns      1V         970mV      1.03V
[Falling Waveform]
R_fixture= 50.000
V_fixture= 1.000
V_fixture_min= 0.970
V_fixture_max= 1.030
|time   V(typ)   V(min)   V(max)
0s        1V         970mV      1.03V
1.228ns   1.001V     970.7mV    1.017V
1.956ns   979.9mV    969.5mV    774.2mV
2.278ns   934.7mV    965.8mV    657.8mV
2.577ns   872.1mV    956.7mV    607.3mV
3.407ns   671.1mV    890.1mV    571.6mV
4.037ns   594mV      807.1mV    563.1mV
5.972ns   539.6mV    591.4mV    555mV
9.493ns   526mV      521.5mV    553.3mV
50ns      523.9mV    505.2mV    553.2mV
[Falling Waveform]
R_fixture= 50.000
V_fixture= 0.0
V_fixture_min= 0.0
V_fixture_max= 0.0
|time   V(typ)   V(min)   V(max)
0s        466.7mV    442.7mV    481.5mV
389ps     468.5mV    443mV      474.6mV
439ps     468.4mV    444.1mV    414.5mV
494ps     453.3mV    445.6mV    284.8mV
573ps     339.9mV    436.1mV    142.2mV
667ps     164mV      344.3mV    64.69mV
763ps     74.78mV    193.3mV    29.98mV
912ps     23.69mV    60.48mV    9.815mV
1.142ns   4.825mV    11.53mV    2.631mV
50ns      1.288uV    6.885uV    590nV
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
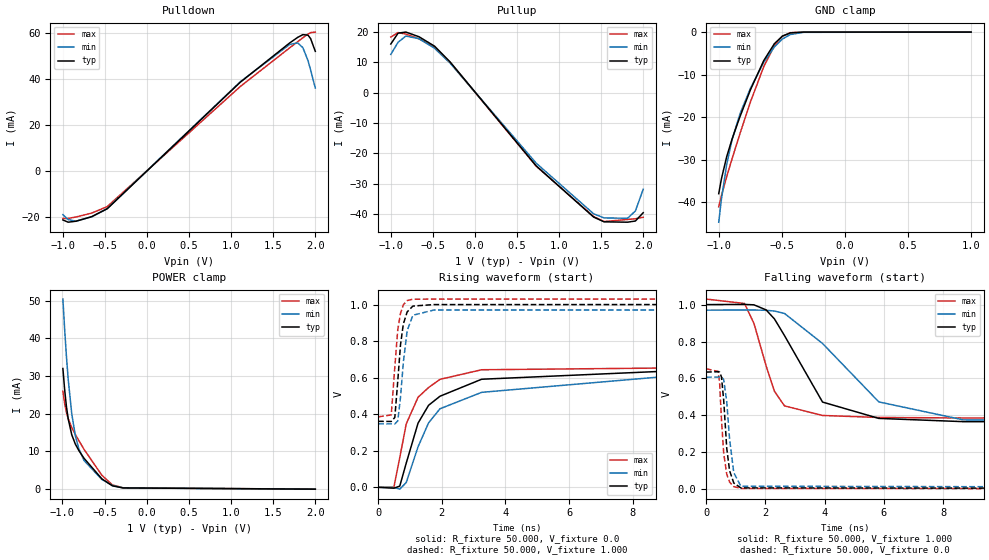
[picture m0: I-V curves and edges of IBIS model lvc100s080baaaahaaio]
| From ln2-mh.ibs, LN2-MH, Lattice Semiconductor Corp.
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|   Model lvc100s080baaaahaaio
[Model] lvc100s080baaaahaaio
| Clamp models do not include dynamic input termination. Please refer to
| the lvc100axxxbaaaahaain model for input termination.
Model_type I/O
Polarity   Non-Inverting
Enable   Active-Low
Vinl =  0.350V
Vinh =  0.650V
Vmeas =  0.500V
Cref =  0.0F
Rref =  1.000M
Vref =  0.0V
C_comp   2.000pF   1.500pF   2.500pF
[Temperature Range]   25.000   0.125k   -40.000
[Voltage Range]   1.000V   0.970V   1.030V
[C Comp Corner]
C_comp   2.000pF   1.500pF   2.500pF
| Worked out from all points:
|   slope of the pulldown table from 0 to 0.15 V, typ, clamps not added: 28.2 ohm
|   slope of the pullup table from 0 to 0.15 V, typ, clamps not added: 28.9 ohm
|   GND clamp passes 1 mA (typ) near -0.50 V on its own axis
|   POWER clamp passes 1 mA (typ) near -0.43 V on its own axis
|   rising waveform, R_fixture 50.000, V_fixture 0.0: 20-80 % time 1.16ns typ, 1.53ns min, 775ps max; typ from 0 V to 0.634 V
|   rising waveform, R_fixture 50.000, V_fixture 1.000: 20-80 % time 192ps typ, 207ps min, 178ps max; typ from 0.361 V to 1 V
|   falling waveform, R_fixture 50.000, V_fixture 1.000: 20-80 % time 1.31ns typ, 2.23ns min, 746ps max; typ from 1 V to 0.361 V
|   falling waveform, R_fixture 50.000, V_fixture 0.0: 20-80 % time 181ps typ, 205ps min, 164ps max; typ from 0.634 V to 0 V
[Pulldown]
|Voltage   I(typ)   I(min)   I(max)
-1V       -21.23mA   -18.93mA   -20.58mA
-938mV    -22.21mA   -21.08mA   -20.59mA
-845mV    -21.79mA   -21.76mA   -19.94mA
-659mV    -19.82mA   -19.89mA   -18.27mA
-473mV    -16.35mA   -16.31mA   -15.42mA
1.108V    38.7mA     38.91mA    36.84mA
1.697V    55.85mA    55.18mA    53.73mA
1.79V     58.22mA    55.84mA    56.33mA
1.852V    59.43mA    53.78mA    58.07mA
1.914V    59.19mA    48.06mA    59.7mA
1.945V    57.65mA    43.97mA    60.3mA
2V        52.16mA    36.18mA    60.54mA
[Pullup]
|Voltage   I(typ)   I(min)   I(max)
-1V       16mA       12.58mA    18.28mA
-914mV    19.57mA    16.56mA    19.76mA
-821mV    19.92mA    18.62mA    19.27mA
-666mV    18.4mA     17.75mA    17.72mA
-480mV    15.29mA    14.6mA     14.9mA
-294mV    10.05mA    9.674mA    9.945mA
729mV     -24.13mA   -23.24mA   -24.23mA
1.411V    -40.95mA   -39.88mA   -40.79mA
1.535V    -42.51mA   -41.22mA   -42.41mA
1.814V    -42.63mA   -41.34mA   -41.73mA
1.907V    -42.24mA   -38.93mA   -41.51mA
2V        -39.51mA   -31.8mA    -41mA
[GND_clamp]
|Voltage   I(typ)   I(min)   I(max)
-1V       -38.04mA   -44.76mA   -41.12mA
-979mV    -34.6mA    -39.43mA   -38.56mA
-937mV    -29.35mA   -31.19mA   -34.05mA
-895mV    -25.25mA   -25.4mA    -29.89mA
-832mV    -19.93mA   -19.28mA   -23.93mA
-748mV    -13.53mA   -13.18mA   -16.39mA
-643mV    -6.699mA   -7.109mA   -8.115mA
-559mV    -2.738mA   -3.494mA   -3.203mA
-496mV    -950.2uA   -1.644mA   -989.9uA
-433mV    -191.7uA   -578.6uA   -139.6uA
-328mV    -5.96uA    -52.93uA   -1.703uA
1V        0A         0A         0A
[POWER_clamp]
|Voltage   I(typ)   I(min)   I(max)
-995mV    32.01mA    50.49mA    25.97mA
-974mV    26.3mA     42.33mA    22.63mA
-953mV    21.89mA    35.2mA     20.31mA
-932mV    18.6mA     29.12mA    18.65mA
-890mV    14.38mA    19.99mA    16.32mA
-848mV    11.92mA    14.19mA    14.49mA
-806mV    10.18mA    10.62mA    12.83mA
-743mV    8.079mA    7.495mA    10.45mA
-533mV    2.652mA    2.481mA    3.608mA
-407mV    775.9uA    886.3uA    1.02mA
-281mV    222uA      236.7uA    263uA
2V        -103.7uA   -104.4uA   -104.8uA
[Ramp]
| variable   typ   min   max
dV/dt_r   0.381/1.162n   0.364/1.526n   0.391/0.775n
dV/dt_f   0.383/1.314n   0.374/2.238n   0.387/0.746n
R_load = 50.000
[Rising Waveform]
R_fixture= 50.000
V_fixture= 0.0
V_fixture_min= 0.0
V_fixture_max= 0.0
|time   V(typ)   V(min)   V(max)
0s        819.6nV    4.423uV    379.7nV
493ps     -4.887mV   -908.7uV   295.1uV
678ps     6.504mV    -10.21mV   162.2mV
882ps     132.6mV    26.25mV    347mV
1.253ns   351.1mV    221.7mV    492.6mV
1.583ns   448.5mV    352.4mV    545.8mV
1.943ns   498.4mV    429.8mV    590.7mV
3.252ns   591.3mV    519.6mV    643.2mV
8.814ns   633.8mV    603.1mV    652.4mV
50ns      634.3mV    606.8mV    652.4mV
[Rising Waveform]
R_fixture= 50.000
V_fixture= 1.000
V_fixture_min= 0.970
V_fixture_max= 1.030
|time   V(typ)   V(min)   V(max)
0s        361mV      347.1mV    385.4mV
411ps     360.3mV    347.1mV    396.1mV
523ps     382.3mV    346.5mV    659mV
615ps     581mV      363.1mV    861.6mV
701ps     779mV      491.8mV    951.9mV
791ps     894.2mV    684.1mV    998.9mV
911ps     959.6mV    857.2mV    1.022V
1.091ns   991.7mV    941.4mV    1.029V
1.752ns   999.9mV    970.1mV    1.03V
50ns      1V         970mV      1.03V
[Falling Waveform]
R_fixture= 50.000
V_fixture= 1.000
V_fixture_min= 0.970
V_fixture_max= 1.030
|time   V(typ)   V(min)   V(max)
0s        1V         970mV      1.03V
1.297ns   1.001V     971mV      1.006V
1.617ns   998.7mV    970.7mV    897.5mV
2.027ns   971.2mV    969.2mV    667.8mV
2.307ns   922.6mV    965.1mV    530.9mV
2.646ns   832.4mV    952.2mV    451.3mV
3.932ns   471.9mV    789.3mV    399.4mV
5.832ns   383.4mV    472.8mV    388.4mV
8.688ns   365.8mV    375.4mV    385.8mV
50ns      361mV      347.1mV    385.4mV
[Falling Waveform]
R_fixture= 50.000
V_fixture= 0.0
V_fixture_min= 0.0
V_fixture_max= 0.0
|time   V(typ)   V(min)   V(max)
0s        634.3mV    606.8mV    652.4mV
410ps     636.3mV    607.4mV    637.7mV
459ps     634mV      608.8mV    568.3mV
519ps     607.9mV    608.5mV    376.8mV
594ps     481mV      593.2mV    194.5mV
697ps     221.4mV    473.4mV    81.62mV
792ps     100.8mV    271.9mV    38.6mV
934ps     33.51mV    89.45mV    13.79mV
1.172ns   6.874mV    16.06mV    3.844mV
50ns      820.6nV    4.427uV    379nV
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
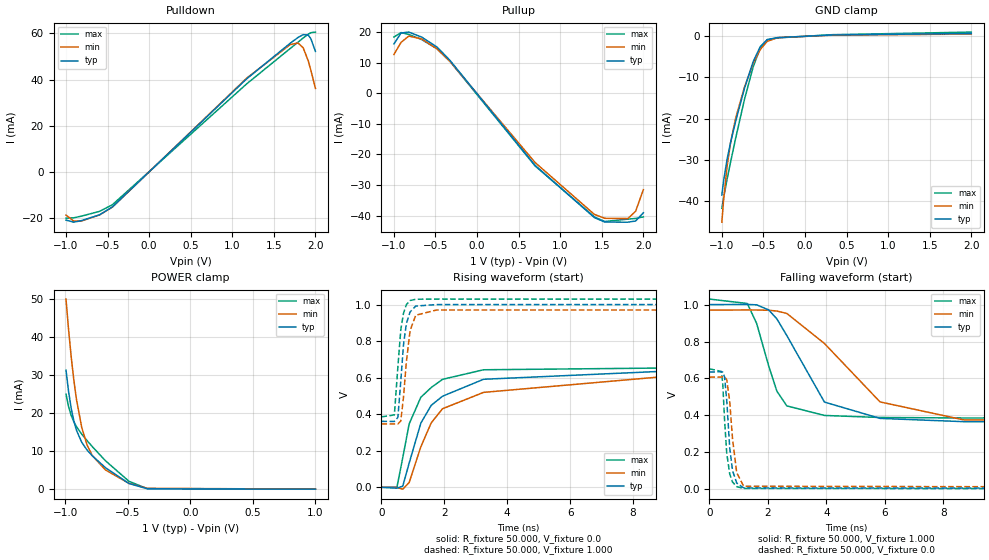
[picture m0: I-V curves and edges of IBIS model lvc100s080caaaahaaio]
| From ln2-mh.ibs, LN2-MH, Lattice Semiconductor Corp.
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|   Model lvc100s080caaaahaaio
[Model] lvc100s080caaaahaaio
| Clamp models do not include dynamic input termination. Please refer to
| the lvc100axxxcaaaahaain model for input termination.
Model_type I/O
Polarity   Non-Inverting
Enable   Active-Low
Vinl =  0.350V
Vinh =  0.650V
Vmeas =  0.500V
Cref =  0.0F
Rref =  1.000M
Vref =  0.0V
C_comp   2.000pF   1.500pF   2.500pF
[Temperature Range]   25.000   0.125k   -40.000
[Voltage Range]   1.000V   0.970V   1.030V
[C Comp Corner]
C_comp   2.000pF   1.500pF   2.500pF
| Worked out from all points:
|   slope of the pulldown table from 0 to 0.15 V, typ, clamps not added: 29 ohm
|   slope of the pullup table from 0 to 0.15 V, typ, clamps not added: 28.6 ohm
|   GND clamp passes 1 mA (typ) near -0.47 V on its own axis
|   POWER clamp passes 1 mA (typ) near -0.46 V on its own axis
|   rising waveform, R_fixture 50.000, V_fixture 0.0: 20-80 % time 1.16ns typ, 1.53ns min, 775ps max; typ from 0 V to 0.634 V
|   rising waveform, R_fixture 50.000, V_fixture 1.000: 20-80 % time 192ps typ, 207ps min, 178ps max; typ from 0.361 V to 1 V
|   falling waveform, R_fixture 50.000, V_fixture 1.000: 20-80 % time 1.31ns typ, 2.23ns min, 746ps max; typ from 1 V to 0.361 V
|   falling waveform, R_fixture 50.000, V_fixture 0.0: 20-80 % time 181ps typ, 205ps min, 164ps max; typ from 0.634 V to 0 V
[Pulldown]
|Voltage   I(typ)   I(min)   I(max)
-1V       -20.79mA   -18.63mA   -20mA
-907mV    -21.71mA   -21.21mA   -19.81mA
-814mV    -21.03mA   -21.21mA   -19.09mA
-597mV    -18.51mA   -18.58mA   -17.03mA
-442mV    -15.1mA    -15.19mA   -14.15mA
1.17V     40.25mA    40.56mA    38.07mA
1.697V    55.78mA    55.17mA    53.5mA
1.79V     58.23mA    55.86mA    56.2mA
1.852V    59.48mA    53.82mA    58mA
1.914V    59.25mA    48.1mA     59.69mA
1.945V    57.72mA    44.01mA    60.31mA
2V        52.22mA    36.21mA    60.58mA
[Pullup]
|Voltage   I(typ)   I(min)   I(max)
-1V       16.06mA    12.61mA    18.33mA
-914mV    19.64mA    16.59mA    19.77mA
-821mV    19.94mA    18.64mA    19.19mA
-666mV    18.3mA     17.7mA     17.49mA
-480mV    15.03mA    14.43mA    14.48mA
-325mV    10.68mA    10.33mA    10.36mA
698mV     -23.6mA    -22.67mA   -23.79mA
1.411V    -40.64mA   -39.61mA   -40.42mA
1.535V    -42.1mA    -40.88mA   -41.92mA
1.814V    -42.15mA   -40.96mA   -41.15mA
1.907V    -41.76mA   -38.58mA   -40.92mA
2V        -39.07mA   -31.52mA   -40.42mA
[GND_clamp]
|Voltage   I(typ)   I(min)   I(max)
-1V       -38.58mA   -45.18mA   -41.8mA
-979mV    -35.16mA   -39.86mA   -39.25mA
-937mV    -29.93mA   -31.65mA   -34.75mA
-895mV    -25.83mA   -25.87mA   -30.59mA
-832mV    -20.52mA   -19.76mA   -24.62mA
-727mV    -12.62mA   -12.32mA   -15.28mA
-622mV    -6.113mA   -6.552mA   -7.373mA
-538mV    -2.537mA   -3.22mA    -2.933mA
-454mV    -801.3uA   -1.232mA   -848.9uA
-328mV    -333.7uA   -332.7uA   -402.2uA
323mV     301.4uA    251.4uA    374.9uA
2V        684.6uA    526.6uA    1.009mA
[POWER_clamp]
|Voltage   I(typ)   I(min)   I(max)
-995mV    31.28mA    49.94mA    24.97mA
-974mV    25.56mA    41.77mA    21.63mA
-953mV    21.15mA    34.64mA    19.32mA
-932mV    17.87mA    28.56mA    17.67mA
-911mV    15.45mA    23.52mA    16.41mA
-869mV    12.3mA     16.19mA    14.45mA
-827mV    10.3mA     11.65mA    12.77mA
-785mV    8.774mA    8.843mA    11.19mA
-680mV    5.655mA    5.063mA    7.48mA
-491mV    1.477mA    1.511mA    2.059mA
-344mV    103.3uA    232.5uA    114.2uA
1V        0A         0A         0A
[Ramp]
| variable   typ   min   max
dV/dt_r   0.381/1.162n   0.364/1.526n   0.391/0.775n
dV/dt_f   0.383/1.314n   0.374/2.238n   0.387/0.746n
R_load = 50.000
[Rising Waveform]
R_fixture= 50.000
V_fixture= 0.0
V_fixture_min= 0.0
V_fixture_max= 0.0
|time   V(typ)   V(min)   V(max)
0s        819.6nV    4.423uV    379.7nV
493ps     -4.887mV   -908.7uV   295.1uV
678ps     6.504mV    -10.21mV   162.2mV
882ps     132.6mV    26.25mV    347mV
1.253ns   351.1mV    221.7mV    492.6mV
1.583ns   448.5mV    352.4mV    545.8mV
1.943ns   498.4mV    429.8mV    590.7mV
3.248ns   591.1mV    519.4mV    643.1mV
8.818ns   633.8mV    603.2mV    652.4mV
50ns      634.3mV    606.8mV    652.4mV
[Rising Waveform]
R_fixture= 50.000
V_fixture= 1.000
V_fixture_min= 0.970
V_fixture_max= 1.030
|time   V(typ)   V(min)   V(max)
0s        361mV      347.1mV    385.4mV
411ps     360.3mV    347.1mV    396.1mV
523ps     382.3mV    346.5mV    659mV
615ps     581mV      363.1mV    861.6mV
701ps     779mV      491.8mV    951.9mV
791ps     894.2mV    684.1mV    998.9mV
911ps     959.6mV    857.2mV    1.022V
1.091ns   991.7mV    941.4mV    1.029V
1.752ns   999.9mV    970.1mV    1.03V
50ns      1V         970mV      1.03V
[Falling Waveform]
R_fixture= 50.000
V_fixture= 1.000
V_fixture_min= 0.970
V_fixture_max= 1.030
|time   V(typ)   V(min)   V(max)
0s        1V         970mV      1.03V
1.297ns   1.001V     971mV      1.006V
1.617ns   998.7mV    970.7mV    897.5mV
2.027ns   971.2mV    969.2mV    667.8mV
2.307ns   922.6mV    965.1mV    530.9mV
2.646ns   832.4mV    952.2mV    451.3mV
3.932ns   471.9mV    789.3mV    399.4mV
5.832ns   383.4mV    472.8mV    388.4mV
8.688ns   365.8mV    375.4mV    385.8mV
50ns      361mV      347.1mV    385.4mV
[Falling Waveform]
R_fixture= 50.000
V_fixture= 0.0
V_fixture_min= 0.0
V_fixture_max= 0.0
|time   V(typ)   V(min)   V(max)
0s        634.3mV    606.8mV    652.4mV
410ps     636.3mV    607.4mV    637.7mV
459ps     634mV      608.8mV    568.3mV
519ps     607.9mV    608.5mV    376.8mV
594ps     481mV      593.2mV    194.5mV
697ps     221.4mV    473.4mV    81.62mV
792ps     100.8mV    271.9mV    38.6mV
934ps     33.51mV    89.45mV    13.79mV
1.172ns   6.874mV    16.06mV    3.844mV
50ns      820.6nV    4.427uV    379nV
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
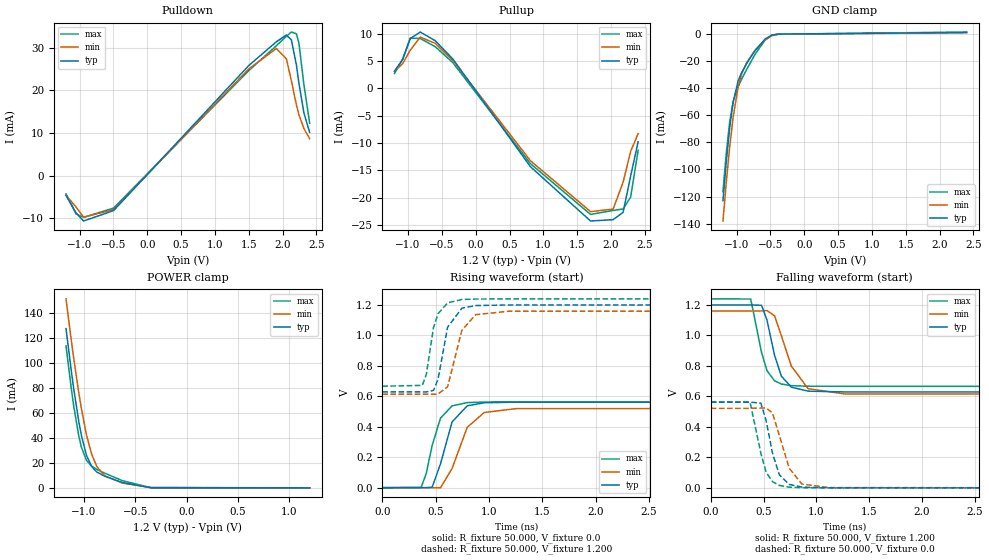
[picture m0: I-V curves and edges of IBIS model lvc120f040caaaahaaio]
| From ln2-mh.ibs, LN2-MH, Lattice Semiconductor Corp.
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|   Model lvc120f040caaaahaaio
[Model] lvc120f040caaaahaaio
| Clamp models do not include dynamic input termination. Please refer to
| the lvc120axxxcaaaahaain model for input termination.
Model_type I/O
Polarity   Non-Inverting
Enable   Active-Low
Vinl =  0.420V
Vinh =  0.780V
Vmeas =  0.600V
Cref =  0.0F
Rref =  1.000M
Vref =  0.0V
C_comp   2.000pF   1.500pF   2.500pF
[Temperature Range]   25.000   0.125k   -40.000
[Voltage Range]   1.200V   1.160V   1.240V
[C Comp Corner]
C_comp   2.000pF   1.500pF   2.500pF
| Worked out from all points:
|   slope of the pulldown table from 0 to 0.18 V, typ, clamps not added: 58 ohm
|   slope of the pullup table from 0 to 0.18 V, typ, clamps not added: 55.7 ohm
|   GND clamp passes 1 mA (typ) near -0.47 V on its own axis
|   POWER clamp passes 1 mA (typ) near -0.46 V on its own axis
|   rising waveform, R_fixture 50.000, V_fixture 0.0: 20-80 % time 137ps typ, 172ps min, 123ps max; typ from 0 V to 0.562 V
|   rising waveform, R_fixture 50.000, V_fixture 1.200: 20-80 % time 97.8ps typ, 120ps min, 91ps max; typ from 0.629 V to 1.2 V
|   falling waveform, R_fixture 50.000, V_fixture 1.200: 20-80 % time 125ps typ, 168ps min, 105ps max; typ from 1.2 V to 0.629 V
|   falling waveform, R_fixture 50.000, V_fixture 0.0: 20-80 % time 111ps typ, 137ps min, 103ps max; typ from 0.562 V to 0 V
[Pulldown]
|Voltage   I(typ)   I(min)   I(max)
-1.2V     -4.694mA   -4.636mA   -4.325mA
-1.052V   -8.754mA   -7.419mA   -9.038mA
-941mV    -10.7mA    -9.794mA   -9.848mA
-497mV    -8.256mA   -8.027mA   -7.655mA
1.501V    25.87mA    25.07mA    24.68mA
1.908V    31.45mA    29.88mA    30.51mA
2.056V    33.03mA    27.43mA    32.75mA
2.13V     31.89mA    22.27mA    33.74mA
2.204V    25.99mA    16.6mA     33.34mA
2.241V    21.71mA    14.32mA    31.14mA
2.315V    14.69mA    11.03mA    21.34mA
2.4V      10.14mA    8.66mA     12.29mA
[Pullup]
|Voltage   I(typ)   I(min)   I(max)
-1.2V     3.124mA    3.061mA    2.691mA
-1.078V   5.308mA    4.516mA    5.332mA
-967mV    9.069mA    6.961mA    9.159mA
-819mV    10.27mA    9.343mA    9.088mA
-597mV    8.674mA    8.198mA    7.579mA
-338mV    5.347mA    5.06mA     4.671mA
809mV     -14.35mA   -13.26mA   -13.8mA
1.697V    -24.28mA   -22.57mA   -23.08mA
2.03V     -24.03mA   -22.1mA    -22.35mA
2.178V    -22.69mA   -17.18mA   -22.08mA
2.289V    -16.07mA   -11.54mA   -19.91mA
2.4V      -9.782mA   -8.302mA   -11.34mA
[GND_clamp]
|Voltage   I(typ)   I(min)   I(max)
-1.2V     -123mA     -137.9mA   -116.3mA
-1.15V    -93.77mA   -109mA     -87.45mA
-1.1V     -69.04mA   -83.2mA    -64.7mA
-1.05V    -50.52mA   -61.66mA   -50.16mA
-975mV    -34.68mA   -39.02mA   -38.92mA
-925mV    -28.78mA   -29.88mA   -33.66mA
-850mV    -22.06mA   -21.38mA   -26.4mA
-725mV    -12.54mA   -12.25mA   -15.19mA
-575mV    -3.931mA   -4.562mA   -4.668mA
-475mV    -1.083mA   -1.617mA   -1.164mA
-375mV    -415.4uA   -497uA     -482.7uA
2.4V      768.5uA    596.7uA    1.09mA
[POWER_clamp]
|Voltage   I(typ)   I(min)   I(max)
-1.175V   127.2mA    151mA      113.4mA
-1.125V   94.42mA    118.8mA    80.34mA
-1.1V     79.34mA    103.6mA    65.54mA
-1.05V    52.82mA    75.75mA    41.2mA
-1.025V   41.91mA    63.3mA     32.44mA
-975mV    25.85mA    42.18mA    21.92mA
-925mV    17.02mA    26.81mA    17.31mA
-875mV    12.68mA    17.07mA    14.77mA
-800mV    9.315mA    9.719mA    11.8mA
-625mV    4.252mA    3.803mA    5.726mA
-350mV    125.8uA    261.6uA    148.8uA
1.2V      0A         0A         0A
[Ramp]
| variable   typ   min   max
dV/dt_r   0.337/0.137n   0.313/0.172n   0.338/0.123n
dV/dt_f   0.343/0.125n   0.328/0.169n   0.344/0.105n
R_load = 50.000
[Rising Waveform]
R_fixture= 50.000
V_fixture= 0.0
V_fixture_min= 0.0
V_fixture_max= 0.0
|time   V(typ)   V(min)   V(max)
0s        1.465uV    7.91uV     665.2nV
364ps     77.49uV    62.84uV    2.067mV
411ps     -373.3uV   76.59uV    90.93mV
467ps     3.067mV    -190.9uV   276.8mV
545ps     155.6mV    -1.163mV   456mV
654ps     432.1mV    126.3mV    537.2mV
796ps     537.7mV    396.5mV    558.7mV
955ps     557.6mV    493.8mV    562.5mV
1.256ns   561.7mV    519.3mV    563.2mV
10ns      562.1mV    521.7mV    563.3mV
[Rising Waveform]
R_fixture= 50.000
V_fixture= 1.200
V_fixture_min= 1.160
V_fixture_max= 1.240
|time   V(typ)   V(min)   V(max)
0s        629.1mV    613.5mV    666.1mV
375ps     629mV      613.6mV    671.9mV
412ps     628.8mV    613.6mV    741.9mV
480ps     638.9mV    613.3mV    1.052V
522ps     711mV      614.6mV    1.142V
612ps     1.054V     663mV      1.214V
746ps     1.179V     1.034V     1.236V
875ps     1.196V     1.136V     1.239V
1.186ns   1.2V       1.159V     1.24V
10ns      1.2V       1.16V      1.24V
[Falling Waveform]
R_fixture= 50.000
V_fixture= 1.200
V_fixture_min= 1.160
V_fixture_max= 1.240
|time   V(typ)   V(min)   V(max)
0s        1.2V       1.16V      1.24V
378ps     1.2V       1.16V      1.239V
481ps     1.198V     1.161V     887.7mV
532ps     1.101V     1.163V     769.1mV
604ps     869.1mV    1.129V     702.4mV
669ps     732.4mV    997.7mV    681.1mV
763ps     660.4mV    797.8mV    670.6mV
922ps     634.5mV    650.4mV    666.9mV
1.269ns   629.3mV    616.1mV    666.2mV
10ns      629mV      613.5mV    666.1mV
[Falling Waveform]
R_fixture= 50.000
V_fixture= 0.0
V_fixture_min= 0.0
V_fixture_max= 0.0
|time   V(typ)   V(min)   V(max)
0s        562mV      521.7mV    563.2mV
372ps     562.6mV    521.7mV    562.7mV
474ps     555.7mV    523.6mV    228mV
523ps     443.6mV    524mV      103.9mV
584ps     228.8mV    492.2mV    40.74mV
649ps     85.98mV    344.7mV    16.07mV
742ps     22.6mV     129.1mV    4.603mV
863ps     4.908mV    25.04mV    1.049mV
1.123ns   359.6uV    1.579mV    92.52uV
10ns      1.484uV    7.938uV    682.6nV
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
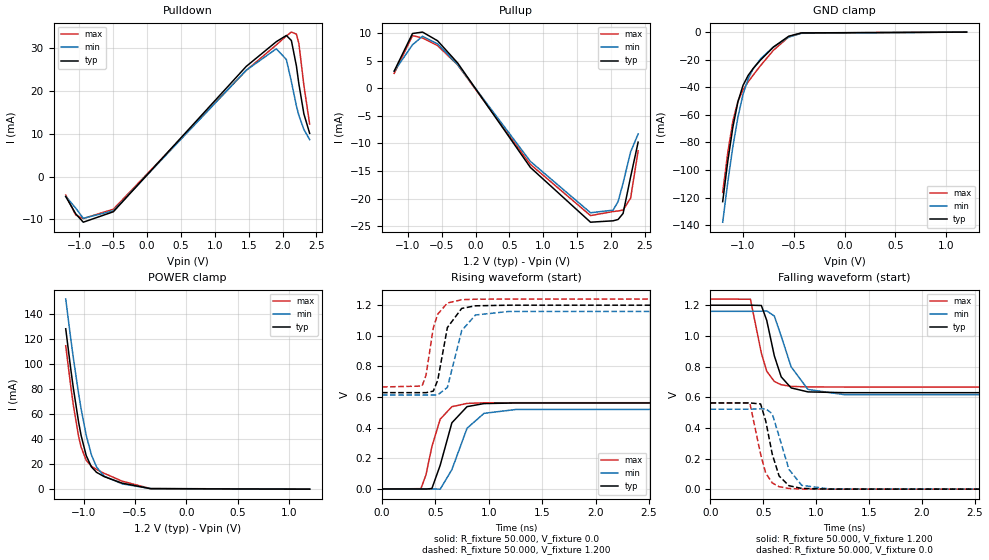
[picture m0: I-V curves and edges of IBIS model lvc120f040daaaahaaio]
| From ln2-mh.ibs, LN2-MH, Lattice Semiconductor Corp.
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|   Model lvc120f040daaaahaaio
[Model] lvc120f040daaaahaaio
| Clamp models do not include dynamic input termination. Please refer to
| the lvc120axxxdaaaahaain model for input termination.
Model_type I/O
Polarity   Non-Inverting
Enable   Active-Low
Vinl =  0.420V
Vinh =  0.780V
Vmeas =  0.600V
Cref =  0.0F
Rref =  1.000M
Vref =  0.0V
C_comp   2.000pF   1.500pF   2.500pF
[Temperature Range]   25.000   0.125k   -40.000
[Voltage Range]   1.200V   1.160V   1.240V
[C Comp Corner]
C_comp   2.000pF   1.500pF   2.500pF
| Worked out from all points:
|   slope of the pulldown table from 0 to 0.18 V, typ, clamps not added: 58 ohm
|   slope of the pullup table from 0 to 0.18 V, typ, clamps not added: 57 ohm
|   GND clamp passes 1 mA (typ) near -0.47 V on its own axis
|   POWER clamp passes 1 mA (typ) near -0.43 V on its own axis
|   rising waveform, R_fixture 50.000, V_fixture 0.0: 20-80 % time 137ps typ, 172ps min, 123ps max; typ from 0 V to 0.562 V
|   rising waveform, R_fixture 50.000, V_fixture 1.200: 20-80 % time 97.8ps typ, 120ps min, 91ps max; typ from 0.629 V to 1.2 V
|   falling waveform, R_fixture 50.000, V_fixture 1.200: 20-80 % time 125ps typ, 168ps min, 105ps max; typ from 1.2 V to 0.629 V
|   falling waveform, R_fixture 50.000, V_fixture 0.0: 20-80 % time 111ps typ, 137ps min, 103ps max; typ from 0.562 V to 0 V
[Pulldown]
|Voltage   I(typ)   I(min)   I(max)
-1.2V     -4.694mA   -4.636mA   -4.325mA
-1.052V   -8.754mA   -7.419mA   -9.038mA
-941mV    -10.7mA    -9.794mA   -9.848mA
-497mV    -8.256mA   -8.027mA   -7.655mA
1.464V    25.8mA     24.91mA    24.86mA
1.908V    31.59mA    29.93mA    30.84mA
2.056V    33.05mA    27.42mA    32.93mA
2.13V     31.87mA    22.26mA    33.84mA
2.204V    25.95mA    16.58mA    33.38mA
2.241V    21.68mA    14.31mA    31.15mA
2.315V    14.66mA    11.01mA    21.33mA
2.4V      10.12mA    8.647mA    12.28mA
[Pullup]
|Voltage   I(typ)   I(min)   I(max)
-1.2V     3.101mA    3.047mA    2.68mA
-930mV    9.902mA    7.862mA    9.519mA
-782mV    10.16mA    9.4mA      9.089mA
-560mV    8.588mA    8.032mA    7.716mA
-264mV    4.568mA    4.273mA    4.221mA
809mV     -14.35mA   -13.26mA   -13.8mA
1.697V    -24.28mA   -22.57mA   -23.08mA
2.03V     -24.03mA   -22.1mA    -22.35mA
2.104V    -23.79mA   -20.55mA   -22.25mA
2.178V    -22.69mA   -17.18mA   -22.08mA
2.289V    -16.07mA   -11.54mA   -19.91mA
2.4V      -9.782mA   -8.302mA   -11.34mA
[GND_clamp]
|Voltage   I(typ)   I(min)   I(max)
-1.2V     -123mA     -137.9mA   -116.3mA
-1.15V    -93.77mA   -109mA     -87.45mA
-1.1V     -69.04mA   -83.2mA    -64.7mA
-1.05V    -50.52mA   -61.66mA   -50.16mA
-1V       -38.68mA   -45.25mA   -41.93mA
-950mV    -31.48mA   -33.96mA   -36.21mA
-900mV    -26.38mA   -26.55mA   -31.19mA
-825mV    -20.04mA   -19.26mA   -24.07mA
-700mV    -10.83mA   -10.73mA   -13.14mA
-550mV    -2.967mA   -3.644mA   -3.468mA
-425mV    -588.2uA   -868.5uA   -635.3uA
1.2V      -845nA     5.241uA    -30.51uA
[POWER_clamp]
|Voltage   I(typ)   I(min)   I(max)
-1.175V   127.9mA    151.6mA    114.4mA
-1.125V   95.2mA     119.4mA    81.41mA
-1.1V     80.12mA    104.2mA    66.6mA
-1.05V    53.6mA     76.35mA    42.26mA
-1.025V   42.7mA     63.91mA    33.48mA
-975mV    26.64mA    42.78mA    22.93mA
-925mV    17.79mA    27.41mA    18.29mA
-875mV    13.42mA    17.66mA    15.69mA
-800mV    9.995mA    10.28mA    12.63mA
-625mV    4.774mA    4.24mA     6.369mA
-350mV    398.5uA    489.6uA    483.6uA
1.2V      0A         0A         49.13uA
[Ramp]
| variable   typ   min   max
dV/dt_r   0.337/0.137n   0.313/0.172n   0.338/0.123n
dV/dt_f   0.343/0.125n   0.328/0.169n   0.344/0.105n
R_load = 50.000
[Rising Waveform]
R_fixture= 50.000
V_fixture= 0.0
V_fixture_min= 0.0
V_fixture_max= 0.0
|time   V(typ)   V(min)   V(max)
0s        1.465uV    7.91uV     665.2nV
364ps     77.49uV    62.84uV    2.067mV
411ps     -373.3uV   76.59uV    90.93mV
467ps     3.067mV    -190.9uV   276.8mV
545ps     155.6mV    -1.163mV   456mV
654ps     432.1mV    126.3mV    537.2mV
796ps     537.7mV    396.5mV    558.7mV
955ps     557.6mV    493.8mV    562.5mV
1.256ns   561.7mV    519.3mV    563.2mV
10ns      562.1mV    521.7mV    563.3mV
[Rising Waveform]
R_fixture= 50.000
V_fixture= 1.200
V_fixture_min= 1.160
V_fixture_max= 1.240
|time   V(typ)   V(min)   V(max)
0s        629.1mV    613.5mV    666.1mV
375ps     629mV      613.6mV    671.9mV
412ps     628.8mV    613.6mV    741.9mV
480ps     638.9mV    613.3mV    1.052V
522ps     711mV      614.6mV    1.142V
612ps     1.054V     663mV      1.214V
746ps     1.179V     1.034V     1.236V
875ps     1.196V     1.136V     1.239V
1.186ns   1.2V       1.159V     1.24V
10ns      1.2V       1.16V      1.24V
[Falling Waveform]
R_fixture= 50.000
V_fixture= 1.200
V_fixture_min= 1.160
V_fixture_max= 1.240
|time   V(typ)   V(min)   V(max)
0s        1.2V       1.16V      1.24V
378ps     1.2V       1.16V      1.239V
481ps     1.198V     1.161V     887.7mV
532ps     1.101V     1.163V     769.1mV
604ps     869.1mV    1.129V     702.4mV
669ps     732.4mV    997.7mV    681.1mV
763ps     660.4mV    797.8mV    670.6mV
922ps     634.5mV    650.4mV    666.9mV
1.269ns   629.3mV    616.1mV    666.2mV
10ns      629mV      613.5mV    666.1mV
[Falling Waveform]
R_fixture= 50.000
V_fixture= 0.0
V_fixture_min= 0.0
V_fixture_max= 0.0
|time   V(typ)   V(min)   V(max)
0s        562mV      521.7mV    563.2mV
372ps     562.6mV    521.7mV    562.7mV
474ps     555.7mV    523.6mV    228mV
523ps     443.6mV    524mV      103.9mV
584ps     228.8mV    492.2mV    40.74mV
649ps     85.98mV    344.7mV    16.07mV
742ps     22.6mV     129.1mV    4.603mV
863ps     4.908mV    25.04mV    1.049mV
1.123ns   359.6uV    1.579mV    92.52uV
10ns      1.484uV    7.938uV    682.6nV
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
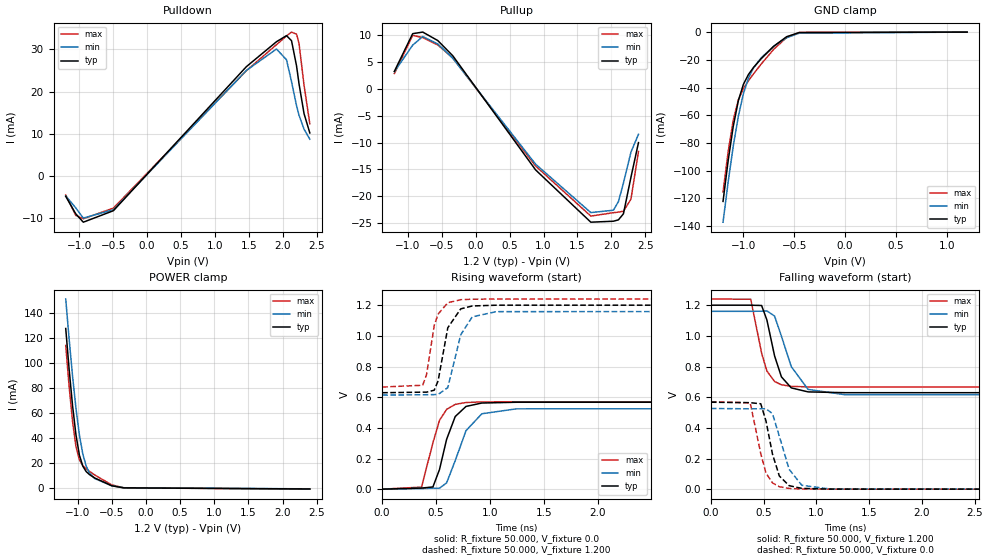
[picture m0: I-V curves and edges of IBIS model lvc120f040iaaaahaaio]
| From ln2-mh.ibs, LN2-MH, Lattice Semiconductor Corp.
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|   Model lvc120f040iaaaahaaio
[Model] lvc120f040iaaaahaaio
| Clamp models do not include dynamic input termination. Please refer to
| the lvc120axxxiaaaahaain model for input termination.
Model_type I/O
Polarity   Non-Inverting
Enable   Active-Low
Vinl =  0.420V
Vinh =  0.780V
Vmeas =  0.600V
Cref =  0.0F
Rref =  1.000M
Vref =  0.0V
C_comp   2.000pF   1.500pF   2.500pF
[Temperature Range]   25.000   0.125k   -40.000
[Voltage Range]   1.200V   1.160V   1.240V
[C Comp Corner]
C_comp   2.000pF   1.500pF   2.500pF
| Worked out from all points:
|   slope of the pulldown table from 0 to 0.18 V, typ, clamps not added: 55.8 ohm
|   slope of the pullup table from 0 to 0.18 V, typ, clamps not added: 55.5 ohm
|   GND clamp passes 1 mA (typ) near -0.50 V on its own axis
|   POWER clamp passes 1 mA (typ) near -0.44 V on its own axis
|   rising waveform, R_fixture 50.000, V_fixture 0.0: 20-80 % time 136ps typ, 171ps min, 121ps max; typ from 0 V to 0.567 V
|   rising waveform, R_fixture 50.000, V_fixture 1.200: 20-80 % time 96.5ps typ, 119ps min, 89.3ps max; typ from 0.629 V to 1.2 V
|   falling waveform, R_fixture 50.000, V_fixture 1.200: 20-80 % time 125ps typ, 168ps min, 105ps max; typ from 1.2 V to 0.629 V
|   falling waveform, R_fixture 50.000, V_fixture 0.0: 20-80 % time 111ps typ, 138ps min, 103ps max; typ from 0.567 V to 0 V
[Pulldown]
|Voltage   I(typ)   I(min)   I(max)
-1.2V     -4.842mA   -4.754mA   -4.504mA
-1.052V   -9.004mA   -7.592mA   -9.375mA
-941mV    -10.98mA   -10mA      -10.17mA
-497mV    -8.254mA   -8.025mA   -7.638mA
1.464V    25.92mA    25.02mA    24.97mA
1.908V    31.84mA    30.11mA    31.14mA
2.056V    33.29mA    27.57mA    33.22mA
2.13V     32.09mA    22.38mA    34.13mA
2.204V    26.12mA    16.67mA    33.64mA
2.241V    21.82mA    14.39mA    31.38mA
2.315V    14.76mA    11.08mA    21.47mA
2.4V      10.19mA    8.701mA    12.37mA
[Pullup]
|Voltage   I(typ)   I(min)   I(max)
-1.2V     3.186mA    3.118mA    2.772mA
-930mV    10.16mA    8.033mA    9.842mA
-782mV    10.45mA    9.621mA    9.433mA
-560mV    8.884mA    8.257mA    8.068mA
-338mV    6.052mA    5.594mA    5.652mA
883mV     -15.08mA   -14.02mA   -14.36mA
1.697V    -24.76mA   -22.98mA   -23.63mA
2.03V     -24.58mA   -22.54mA   -23mA
2.104V    -24.33mA   -20.95mA   -22.9mA
2.178V    -23.21mA   -17.52mA   -22.73mA
2.289V    -16.43mA   -11.78mA   -20.5mA
2.4V      -10.02mA   -8.478mA   -11.68mA
[GND_clamp]
|Voltage   I(typ)   I(min)   I(max)
-1.2V     -122.1mA   -137.1mA   -115.3mA
-1.15V    -92.88mA   -108.2mA   -86.34mA
-1.1V     -68.13mA   -82.44mA   -63.55mA
-1.05V    -49.58mA   -60.89mA   -48.98mA
-1V       -37.73mA   -44.48mA   -40.75mA
-950mV    -30.55mA   -33.19mA   -35.07mA
-900mV    -25.48mA   -25.79mA   -30.1mA
-825mV    -19.21mA   -18.55mA   -23.07mA
-700mV    -10.12mA   -10.12mA   -12.27mA
-575mV    -3.338mA   -4.053mA   -3.949mA
-450mV    -310.5uA   -787.2uA   -256.6uA
1.2V      0A         0A         0A
[POWER_clamp]
|Voltage   I(typ)   I(min)   I(max)
-1.175V   127.9mA    151.5mA    114.4mA
-1.125V   95.11mA    119.3mA    81.3mA
-1.075V   66.05mA    89.76mA    53.26mA
-1.025V   42.55mA    63.81mA    33.28mA
-975mV    26.45mA    42.66mA    22.68mA
-925mV    17.56mA    27.27mA    18.01mA
-875mV    13.18mA    17.5mA     15.4mA
-825mV    10.7mA     11.9mA     13.32mA
-750mV    8.076mA    7.611mA    10.45mA
-500mV    1.821mA    1.817mA    2.516mA
-325mV    164.5uA    258.7uA    189uA
2.4V      -731uA     -642.7uA   -887.3uA
[Ramp]
| variable   typ   min   max
dV/dt_r   0.340/0.136n   0.316/0.171n   0.342/0.122n
dV/dt_f   0.343/0.125n   0.328/0.169n   0.344/0.105n
R_load = 50.000
[Rising Waveform]
R_fixture= 50.000
V_fixture= 0.0
V_fixture_min= 0.0
V_fixture_max= 0.0
|time   V(typ)   V(min)   V(max)
0s        1.465uV    7.91uV     665.2nV
365ps     7.119mV    3.932mV    13.33mV
471ps     14.48mV    6.638mV    302.8mV
532ps     128.3mV    6.382mV    448.9mV
598ps     325.1mV    40.95mV    520.6mV
678ps     474mV      186.5mV    553mV
778ps     539.7mV    381.7mV    565.2mV
925ps     561.9mV    491.8mV    569.1mV
1.246ns   566.9mV    523.9mV    569.9mV
10ns      567.2mV    526.4mV    570mV
[Rising Waveform]
R_fixture= 50.000
V_fixture= 1.200
V_fixture_min= 1.160
V_fixture_max= 1.240
|time   V(typ)   V(min)   V(max)
0s        629.1mV    613.5mV    666.1mV
376ps     632.7mV    615.7mV    677.8mV
412ps     632.8mV    616.3mV    747.5mV
483ps     645.5mV    616.7mV    1.067V
519ps     706.3mV    618mV      1.142V
609ps     1.053V     662.2mV    1.216V
729ps     1.176V     1.007V     1.236V
836ps     1.195V     1.124V     1.239V
1.06ns    1.2V       1.158V     1.24V
10ns      1.2V       1.16V      1.24V
[Falling Waveform]
R_fixture= 50.000
V_fixture= 1.200
V_fixture_min= 1.160
V_fixture_max= 1.240
|time   V(typ)   V(min)   V(max)
0s        1.2V       1.16V      1.24V
378ps     1.2V       1.16V      1.239V
481ps     1.198V     1.161V     887.6mV
531ps     1.104V     1.163V     770.6mV
604ps     869mV      1.129V     702.4mV
669ps     732.3mV    997.6mV    681mV
762ps     660.7mV    799.5mV    670.7mV
921ps     634.5mV    650.8mV    666.9mV
1.272ns   629.3mV    616.1mV    666.2mV
10ns      629mV      613.5mV    666.1mV
[Falling Waveform]
R_fixture= 50.000
V_fixture= 0.0
V_fixture_min= 0.0
V_fixture_max= 0.0
|time   V(typ)   V(min)   V(max)
0s        567.1mV    526.3mV    570mV
373ps     564.2mV    524.1mV    563.1mV
473ps     556.9mV    524.4mV    231.5mV
523ps     443.8mV    524.5mV    104mV
584ps     228.8mV    492.5mV    40.8mV
649ps     86mV       344.9mV    16.08mV
742ps     22.77mV    129.1mV    4.609mV
862ps     5.142mV    25.37mV    1.064mV
1.122ns   337.4uV    1.595mV    93.52uV
10ns      1.484uV    7.938uV    682.5nV
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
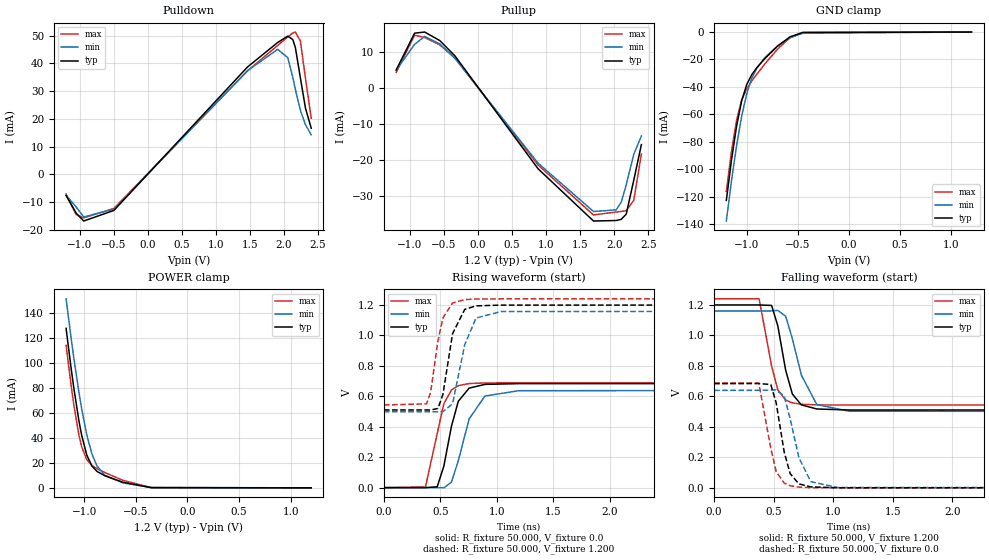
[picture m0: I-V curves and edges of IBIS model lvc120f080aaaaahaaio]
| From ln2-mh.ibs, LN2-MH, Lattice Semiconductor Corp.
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|   Model lvc120f080aaaaahaaio
[Model] lvc120f080aaaaahaaio
| Clamp models do not include dynamic input termination. Please refer to
| the lvc120axxxaaaaahaain model for input termination.
Model_type I/O
Polarity   Non-Inverting
Enable   Active-Low
Vinl =  0.420V
Vinh =  0.780V
Vmeas =  0.600V
Cref =  0.0F
Rref =  1.000M
Vref =  0.0V
C_comp   2.000pF   1.500pF   2.500pF
[Temperature Range]   25.000   0.125k   -40.000
[Voltage Range]   1.200V   1.160V   1.240V
[C Comp Corner]
C_comp   2.000pF   1.500pF   2.500pF
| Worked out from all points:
|   slope of the pulldown table from 0 to 0.18 V, typ, clamps not added: 36.9 ohm
|   slope of the pullup table from 0 to 0.18 V, typ, clamps not added: 37.3 ohm
|   GND clamp passes 1 mA (typ) near -0.50 V on its own axis
|   POWER clamp passes 1 mA (typ) near -0.45 V on its own axis
|   rising waveform, R_fixture 50.000, V_fixture 0.0: 20-80 % time 119ps typ, 147ps min, 109ps max; typ from 0 V to 0.684 V
|   rising waveform, R_fixture 50.000, V_fixture 1.200: 20-80 % time 94.4ps typ, 111ps min, 92ps max; typ from 0.51 V to 1.2 V
|   falling waveform, R_fixture 50.000, V_fixture 1.200: 20-80 % time 106ps typ, 140ps min, 93.6ps max; typ from 1.2 V to 0.51 V
|   falling waveform, R_fixture 50.000, V_fixture 0.0: 20-80 % time 95.2ps typ, 119ps min, 89.4ps max; typ from 0.684 V to 0 V
[Pulldown]
|Voltage   I(typ)   I(min)   I(max)
-1.2V     -7.643mA   -7.514mA   -7.124mA
-1.052V   -13.98mA   -11.81mA   -14.55mA
-941mV    -16.85mA   -15.38mA   -15.73mA
-497mV    -13.02mA   -12.56mA   -12.29mA
1.464V    38.7mA     37.38mA    37.29mA
1.908V    47.55mA    45.08mA    46.49mA
2.056V    49.83mA    42.04mA    49.58mA
2.13V     48.57mA    34.91mA    50.98mA
2.167V    45.71mA    30.58mA    51.31mA
2.241V    34.72mA    23.01mA    48.07mA
2.315V    23.86mA    17.9mA     34.66mA
2.4V      16.59mA    14.23mA    20.22mA
[Pullup]
|Voltage   I(typ)   I(min)   I(max)
-1.2V     5.078mA    5mA        4.395mA
-930mV    15.33mA    12.22mA    14.77mA
-782mV    15.65mA    14.42mA    14.12mA
-560mV    13.27mA    12.33mA    12.06mA
-338mV    9.009mA    8.335mA    8.419mA
883mV     -22.47mA   -20.9mA    -21.41mA
1.697V    -37.04mA   -34.39mA   -35.35mA
2.03V     -36.9mA    -33.94mA   -34.53mA
2.104V    -36.58mA   -31.79mA   -34.38mA
2.178V    -35.11mA   -26.95mA   -34.15mA
2.289V    -25.61mA   -18.39mA   -31.24mA
2.4V      -15.75mA   -13.34mA   -18.38mA
[GND_clamp]
|Voltage   I(typ)   I(min)   I(max)
-1.2V     -122.7mA   -137.7mA   -116.1mA
-1.15V    -93.51mA   -108.7mA   -87.11mA
-1.1V     -68.71mA   -82.95mA   -64.25mA
-1.05V    -50.11mA   -61.37mA   -49.6mA
-1V       -38.2mA    -44.91mA   -41.31mA
-950mV    -30.97mA   -33.58mA   -35.58mA
-900mV    -25.86mA   -26.14mA   -30.55mA
-825mV    -19.51mA   -18.84mA   -23.44mA
-700mV    -10.31mA   -10.31mA   -12.51mA
-575mV    -3.428mA   -4.153mA   -4.057mA
-450mV    -324.6uA   -816.9uA   -269.6uA
1.2V      0A         0A         0A
[POWER_clamp]
|Voltage   I(typ)   I(min)   I(max)
-1.175V   127.9mA    151.5mA    114.3mA
-1.125V   95.1mA     119.3mA    81.28mA
-1.1V     80mA       104.1mA    66.45mA
-1.05V    53.45mA    76.24mA    42.06mA
-1.025V   42.52mA    63.79mA    33.25mA
-975mV    26.41mA    42.63mA    22.64mA
-925mV    17.53mA    27.24mA    17.96mA
-875mV    13.14mA    17.46mA    15.36mA
-800mV    9.702mA    10.06mA    12.29mA
-625mV    4.476mA    4.013mA    6.017mA
-350mV    147.7uA    296.5uA    176.7uA
1.2V      0A         0A         0A
[Ramp]
| variable   typ   min   max
dV/dt_r   0.410/0.119n   0.384/0.147n   0.413/0.109n
dV/dt_f   0.414/0.106n   0.397/0.140n   0.418/93.739p
R_load = 50.000
[Rising Waveform]
R_fixture= 50.000
V_fixture= 0.0
V_fixture_min= 0.0
V_fixture_max= 0.0
|time   V(typ)   V(min)   V(max)
0s        1.143uV    6.223uV    521.7nV
368ps     64uV       47.01uV    4.907mV
472ps     5.652mV    -291.3uV   355.1mV
531ps     141.7mV    -1.28mV    551.2mV
598ps     402.6mV    35.91mV    641.7mV
659ps     567.3mV    177mV      670mV
755ps     653.9mV    451.4mV    683.8mV
895ps     678.3mV    601.7mV    687.8mV
1.195ns   683.3mV    637mV      688.6mV
10ns      683.6mV    639.6mV    688.7mV
[Rising Waveform]
R_fixture= 50.000
V_fixture= 1.200
V_fixture_min= 1.160
V_fixture_max= 1.240
|time   V(typ)   V(min)   V(max)
0s        510.2mV    498.2mV    543.2mV
377ps     510.2mV    498.3mV    550.1mV
413ps     509.9mV    498.3mV    623.7mV
479ps     520.2mV    497.9mV    966.5mV
523ps     613.5mV    499.1mV    1.116V
608ps     1.011V     550.8mV    1.213V
716ps     1.171V     939.6mV    1.235V
816ps     1.194V     1.114V     1.239V
1.036ns   1.199V     1.157V     1.24V
10ns      1.2V       1.16V      1.24V
[Falling Waveform]
R_fixture= 50.000
V_fixture= 1.200
V_fixture_min= 1.160
V_fixture_max= 1.240
|time   V(typ)   V(min)   V(max)
0s        1.2V       1.16V      1.24V
378ps     1.2V       1.16V      1.24V
483ps     1.197V     1.161V     799.3mV
535ps     1.063V     1.164V     643.1mV
601ps     771.9mV    1.126V     576.4mV
657ps     616.2mV    979.8mV    557.6mV
732ps     544.7mV    741.4mV    548.6mV
862ps     517.5mV    546.6mV    544.5mV
1.132ns   510.9mV    503mV      543.4mV
10ns      510.2mV    498.2mV    543.2mV
[Falling Waveform]
R_fixture= 50.000
V_fixture= 0.0
V_fixture_min= 0.0
V_fixture_max= 0.0
|time   V(typ)   V(min)   V(max)
0s        683.6mV    639.6mV    688.7mV
376ps     684.2mV    639.7mV    686.9mV
476ps     678mV      641.7mV    259.1mV
521ps     559mV      642.8mV    107.3mV
589ps     233.9mV    601.8mV    31.07mV
639ps     93.3mV     453.3mV    13.88mV
712ps     26.09mV    198.2mV    4.71mV
812ps     6.322mV    40.22mV    1.247mV
1.038ns   543.1uV    2.51mV     129.1uV
10ns      1.156uV    6.238uV    534.1nV
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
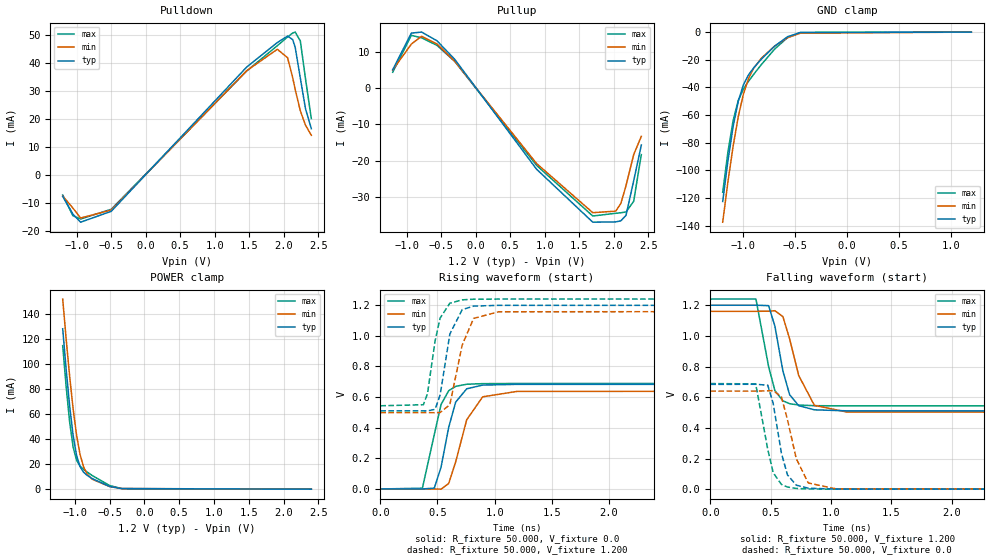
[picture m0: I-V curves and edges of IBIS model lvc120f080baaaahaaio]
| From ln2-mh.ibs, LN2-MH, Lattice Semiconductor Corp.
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|   Model lvc120f080baaaahaaio
[Model] lvc120f080baaaahaaio
| Clamp models do not include dynamic input termination. Please refer to
| the lvc120axxxbaaaahaain model for input termination.
Model_type I/O
Polarity   Non-Inverting
Enable   Active-Low
Vinl =  0.420V
Vinh =  0.780V
Vmeas =  0.600V
Cref =  0.0F
Rref =  1.000M
Vref =  0.0V
C_comp   2.000pF   1.500pF   2.500pF
[Temperature Range]   25.000   0.125k   -40.000
[Voltage Range]   1.200V   1.160V   1.240V
[C Comp Corner]
C_comp   2.000pF   1.500pF   2.500pF
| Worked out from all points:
|   slope of the pulldown table from 0 to 0.18 V, typ, clamps not added: 36.9 ohm
|   slope of the pullup table from 0 to 0.18 V, typ, clamps not added: 38 ohm
|   GND clamp passes 1 mA (typ) near -0.50 V on its own axis
|   POWER clamp passes 1 mA (typ) near -0.43 V on its own axis
|   rising waveform, R_fixture 50.000, V_fixture 0.0: 20-80 % time 119ps typ, 147ps min, 109ps max; typ from 0 V to 0.684 V
|   rising waveform, R_fixture 50.000, V_fixture 1.200: 20-80 % time 94.4ps typ, 111ps min, 92ps max; typ from 0.51 V to 1.2 V
|   falling waveform, R_fixture 50.000, V_fixture 1.200: 20-80 % time 106ps typ, 140ps min, 93.6ps max; typ from 1.2 V to 0.51 V
|   falling waveform, R_fixture 50.000, V_fixture 0.0: 20-80 % time 95.2ps typ, 119ps min, 89.4ps max; typ from 0.684 V to 0 V
[Pulldown]
|Voltage   I(typ)   I(min)   I(max)
-1.2V     -7.635mA   -7.505mA   -7.116mA
-1.052V   -13.96mA   -11.8mA    -14.53mA
-941mV    -16.83mA   -15.35mA   -15.7mA
-497mV    -12.94mA   -12.49mA   -12.21mA
1.464V    38.5mA     37.2mA     37.09mA
1.908V    47.25mA    44.85mA    46.14mA
2.056V    49.55mA    41.85mA    49.24mA
2.13V     48.31mA    34.76mA    50.65mA
2.167V    45.48mA    30.45mA    50.98mA
2.241V    34.55mA    22.91mA    47.8mA
2.315V    23.74mA    17.82mA    34.49mA
2.4V      16.51mA    14.16mA    20.11mA
[Pullup]
|Voltage   I(typ)   I(min)   I(max)
-1.2V     4.994mA    4.929mA    4.304mA
-930mV    15.07mA    12.05mA    14.45mA
-782mV    15.35mA    14.2mA     13.78mA
-560mV    12.97mA    12.11mA    11.71mA
-301mV    7.84mA     7.308mA    7.274mA
883mV     -22.37mA   -20.8mA    -21.31mA
1.697V    -36.95mA   -34.33mA   -35.25mA
2.03V     -36.87mA   -33.91mA   -34.5mA
2.104V    -36.56mA   -31.77mA   -34.36mA
2.178V    -35.08mA   -26.93mA   -34.13mA
2.289V    -25.6mA    -18.38mA   -31.23mA
2.4V      -15.74mA   -13.33mA   -18.37mA
[GND_clamp]
|Voltage   I(typ)   I(min)   I(max)
-1.2V     -122.6mA   -137.6mA   -116mA
-1.15V    -93.41mA   -108.6mA   -87.01mA
-1.1V     -68.62mA   -82.86mA   -64.16mA
-1.05V    -50.02mA   -61.28mA   -49.51mA
-1V       -38.12mA   -44.82mA   -41.23mA
-950mV    -30.88mA   -33.5mA    -35.49mA
-900mV    -25.78mA   -26.06mA   -30.47mA
-825mV    -19.44mA   -18.76mA   -23.36mA
-700mV    -10.25mA   -10.24mA   -12.44mA
-575mV    -3.381mA   -4.102mA   -4.007mA
-450mV    -315.1uA   -796.4uA   -262uA
1.2V      0A         0A         0A
[POWER_clamp]
|Voltage   I(typ)   I(min)   I(max)
-1.175V   127.9mA    151.6mA    114.4mA
-1.125V   95.2mA     119.4mA    81.41mA
-1.075V   66.17mA    89.85mA    53.4mA
-1.025V   42.7mA     63.91mA    33.48mA
-975mV    26.64mA    42.78mA    22.93mA
-925mV    17.79mA    27.41mA    18.29mA
-875mV    13.42mA    17.66mA    15.69mA
-825mV    10.95mA    12.07mA    13.61mA
-750mV    8.323mA    7.791mA    10.74mA
-500mV    2.04mA     1.98mA     2.782mA
-325mV    310.3uA    373.2uA    366.8uA
2.4V      -105uA     -106.2uA   -106.1uA
[Ramp]
| variable   typ   min   max
dV/dt_r   0.410/0.119n   0.384/0.147n   0.413/0.109n
dV/dt_f   0.414/0.106n   0.397/0.140n   0.418/93.739p
R_load = 50.000
[Rising Waveform]
R_fixture= 50.000
V_fixture= 0.0
V_fixture_min= 0.0
V_fixture_max= 0.0
|time   V(typ)   V(min)   V(max)
0s        1.143uV    6.223uV    521.7nV
368ps     64uV       47.01uV    4.907mV
472ps     5.652mV    -291.3uV   355.1mV
531ps     141.7mV    -1.28mV    551.2mV
598ps     402.6mV    35.91mV    641.7mV
659ps     567.3mV    177mV      670mV
755ps     653.9mV    451.4mV    683.8mV
895ps     678.3mV    601.7mV    687.8mV
1.195ns   683.3mV    637mV      688.6mV
10ns      683.6mV    639.6mV    688.7mV
[Rising Waveform]
R_fixture= 50.000
V_fixture= 1.200
V_fixture_min= 1.160
V_fixture_max= 1.240
|time   V(typ)   V(min)   V(max)
0s        510.2mV    498.2mV    543.2mV
377ps     510.2mV    498.3mV    550.1mV
413ps     509.9mV    498.3mV    623.7mV
479ps     520.2mV    497.9mV    966.5mV
523ps     613.5mV    499.1mV    1.116V
608ps     1.011V     550.8mV    1.213V
716ps     1.171V     939.6mV    1.235V
816ps     1.194V     1.114V     1.239V
1.036ns   1.199V     1.157V     1.24V
10ns      1.2V       1.16V      1.24V
[Falling Waveform]
R_fixture= 50.000
V_fixture= 1.200
V_fixture_min= 1.160
V_fixture_max= 1.240
|time   V(typ)   V(min)   V(max)
0s        1.2V       1.16V      1.24V
378ps     1.2V       1.16V      1.24V
483ps     1.197V     1.161V     799.3mV
535ps     1.063V     1.164V     643.1mV
601ps     771.9mV    1.126V     576.4mV
657ps     616.2mV    979.8mV    557.6mV
732ps     544.7mV    741.4mV    548.6mV
862ps     517.5mV    546.6mV    544.5mV
1.132ns   510.9mV    503mV      543.4mV
10ns      510.2mV    498.2mV    543.2mV
[Falling Waveform]
R_fixture= 50.000
V_fixture= 0.0
V_fixture_min= 0.0
V_fixture_max= 0.0
|time   V(typ)   V(min)   V(max)
0s        683.6mV    639.6mV    688.7mV
376ps     684.2mV    639.7mV    686.9mV
476ps     678mV      641.7mV    259.1mV
521ps     559mV      642.8mV    107.3mV
589ps     233.9mV    601.8mV    31.07mV
639ps     93.3mV     453.3mV    13.88mV
712ps     26.09mV    198.2mV    4.71mV
812ps     6.322mV    40.22mV    1.247mV
1.038ns   543.1uV    2.51mV     129.1uV
10ns      1.156uV    6.238uV    534.1nV
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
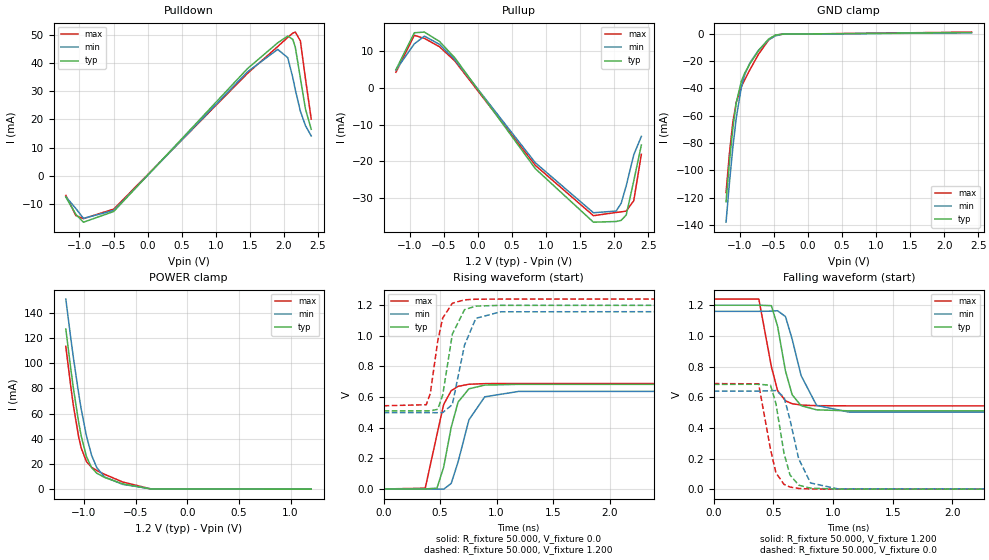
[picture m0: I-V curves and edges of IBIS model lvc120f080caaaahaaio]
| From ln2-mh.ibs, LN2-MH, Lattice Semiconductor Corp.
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|   Model lvc120f080caaaahaaio
[Model] lvc120f080caaaahaaio
| Clamp models do not include dynamic input termination. Please refer to
| the lvc120axxxcaaaahaain model for input termination.
Model_type I/O
Polarity   Non-Inverting
Enable   Active-Low
Vinl =  0.420V
Vinh =  0.780V
Vmeas =  0.600V
Cref =  0.0F
Rref =  1.000M
Vref =  0.0V
C_comp   2.000pF   1.500pF   2.500pF
[Temperature Range]   25.000   0.125k   -40.000
[Voltage Range]   1.200V   1.160V   1.240V
[C Comp Corner]
C_comp   2.000pF   1.500pF   2.500pF
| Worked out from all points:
|   slope of the pulldown table from 0 to 0.18 V, typ, clamps not added: 38.3 ohm
|   slope of the pullup table from 0 to 0.18 V, typ, clamps not added: 37.4 ohm
|   GND clamp passes 1 mA (typ) near -0.47 V on its own axis
|   POWER clamp passes 1 mA (typ) near -0.46 V on its own axis
|   rising waveform, R_fixture 50.000, V_fixture 0.0: 20-80 % time 119ps typ, 147ps min, 109ps max; typ from 0 V to 0.684 V
|   rising waveform, R_fixture 50.000, V_fixture 1.200: 20-80 % time 94.4ps typ, 111ps min, 92ps max; typ from 0.51 V to 1.2 V
|   falling waveform, R_fixture 50.000, V_fixture 1.200: 20-80 % time 106ps typ, 140ps min, 93.6ps max; typ from 1.2 V to 0.51 V
|   falling waveform, R_fixture 50.000, V_fixture 0.0: 20-80 % time 95.2ps typ, 119ps min, 89.4ps max; typ from 0.684 V to 0 V
[Pulldown]
|Voltage   I(typ)   I(min)   I(max)
-1.2V     -7.419mA   -7.327mA   -6.854mA
-1.052V   -13.57mA   -11.52mA   -13.99mA
-941mV    -16.34mA   -14.99mA   -15.09mA
-497mV    -12.55mA   -12.17mA   -11.71mA
1.464V    37.98mA    36.83mA    36.29mA
1.908V    47.11mA    44.8mA     45.8mA
2.056V    49.53mA    41.86mA    49.06mA
2.13V     48.33mA    34.77mA    50.55mA
2.167V    45.51mA    30.47mA    50.92mA
2.241V    34.59mA    22.92mA    47.79mA
2.315V    23.77mA    17.84mA    34.5mA
2.4V      16.53mA    14.18mA    20.13mA
[Pullup]
|Voltage   I(typ)   I(min)   I(max)
-1.2V     5.016mA    4.942mA    4.314mA
-930mV    15.09mA    12.07mA    14.39mA
-782mV    15.27mA    14.17mA    13.56mA
-560mV    12.7mA     11.92mA    11.26mA
-338mV    8.302mA    7.8mA      7.436mA
846mV     -21.99mA   -20.38mA   -21.08mA
1.697V    -36.56mA   -33.99mA   -34.79mA
2.03V     -36.37mA   -33.52mA   -33.9mA
2.104V    -36.06mA   -31.4mA    -33.75mA
2.178V    -34.61mA   -26.63mA   -33.52mA
2.289V    -25.26mA   -18.17mA   -30.68mA
2.4V      -15.52mA   -13.17mA   -18.06mA
[GND_clamp]
|Voltage   I(typ)   I(min)   I(max)
-1.2V     -123mA     -137.9mA   -116.3mA
-1.15V    -93.77mA   -109mA     -87.45mA
-1.1V     -69.04mA   -83.2mA    -64.7mA
-1.05V    -50.52mA   -61.66mA   -50.16mA
-975mV    -34.68mA   -39.02mA   -38.92mA
-925mV    -28.78mA   -29.88mA   -33.66mA
-850mV    -22.06mA   -21.38mA   -26.4mA
-725mV    -12.54mA   -12.25mA   -15.19mA
-575mV    -3.931mA   -4.562mA   -4.668mA
-475mV    -1.083mA   -1.617mA   -1.164mA
-375mV    -415.4uA   -497uA     -482.7uA
2.4V      768.5uA    596.7uA    1.09mA
[POWER_clamp]
|Voltage   I(typ)   I(min)   I(max)
-1.175V   127.2mA    151mA      113.4mA
-1.125V   94.42mA    118.8mA    80.34mA
-1.1V     79.34mA    103.6mA    65.54mA
-1.05V    52.82mA    75.75mA    41.2mA
-1.025V   41.91mA    63.3mA     32.44mA
-975mV    25.85mA    42.18mA    21.92mA
-925mV    17.02mA    26.81mA    17.31mA
-875mV    12.68mA    17.07mA    14.77mA
-800mV    9.315mA    9.719mA    11.8mA
-625mV    4.252mA    3.803mA    5.726mA
-350mV    125.8uA    261.6uA    148.8uA
1.2V      0A         0A         0A
[Ramp]
| variable   typ   min   max
dV/dt_r   0.410/0.119n   0.384/0.147n   0.413/0.109n
dV/dt_f   0.414/0.106n   0.397/0.140n   0.418/93.739p
R_load = 50.000
[Rising Waveform]
R_fixture= 50.000
V_fixture= 0.0
V_fixture_min= 0.0
V_fixture_max= 0.0
|time   V(typ)   V(min)   V(max)
0s        1.143uV    6.223uV    521.7nV
368ps     64uV       47.01uV    4.907mV
472ps     5.652mV    -291.3uV   355.1mV
531ps     141.7mV    -1.28mV    551.2mV
598ps     402.6mV    35.91mV    641.7mV
659ps     567.3mV    177mV      670mV
755ps     653.9mV    451.4mV    683.8mV
895ps     678.3mV    601.7mV    687.8mV
1.195ns   683.3mV    637mV      688.6mV
10ns      683.6mV    639.6mV    688.7mV
[Rising Waveform]
R_fixture= 50.000
V_fixture= 1.200
V_fixture_min= 1.160
V_fixture_max= 1.240
|time   V(typ)   V(min)   V(max)
0s        510.2mV    498.2mV    543.2mV
377ps     510.2mV    498.3mV    550.1mV
413ps     509.9mV    498.3mV    623.7mV
479ps     520.2mV    497.9mV    966.5mV
523ps     613.5mV    499.1mV    1.116V
608ps     1.011V     550.8mV    1.213V
716ps     1.171V     939.6mV    1.235V
816ps     1.194V     1.114V     1.239V
1.036ns   1.199V     1.157V     1.24V
10ns      1.2V       1.16V      1.24V
[Falling Waveform]
R_fixture= 50.000
V_fixture= 1.200
V_fixture_min= 1.160
V_fixture_max= 1.240
|time   V(typ)   V(min)   V(max)
0s        1.2V       1.16V      1.24V
378ps     1.2V       1.16V      1.24V
483ps     1.197V     1.161V     799.3mV
535ps     1.063V     1.164V     643.1mV
601ps     771.9mV    1.126V     576.4mV
657ps     616.2mV    979.8mV    557.6mV
732ps     544.7mV    741.4mV    548.6mV
862ps     517.5mV    546.6mV    544.5mV
1.132ns   510.9mV    503mV      543.4mV
10ns      510.2mV    498.2mV    543.2mV
[Falling Waveform]
R_fixture= 50.000
V_fixture= 0.0
V_fixture_min= 0.0
V_fixture_max= 0.0
|time   V(typ)   V(min)   V(max)
0s        683.6mV    639.6mV    688.7mV
376ps     684.2mV    639.7mV    686.9mV
476ps     678mV      641.7mV    259.1mV
521ps     559mV      642.8mV    107.3mV
589ps     233.9mV    601.8mV    31.07mV
639ps     93.3mV     453.3mV    13.88mV
712ps     26.09mV    198.2mV    4.71mV
812ps     6.322mV    40.22mV    1.247mV
1.038ns   543.1uV    2.51mV     129.1uV
10ns      1.156uV    6.238uV    534.1nV
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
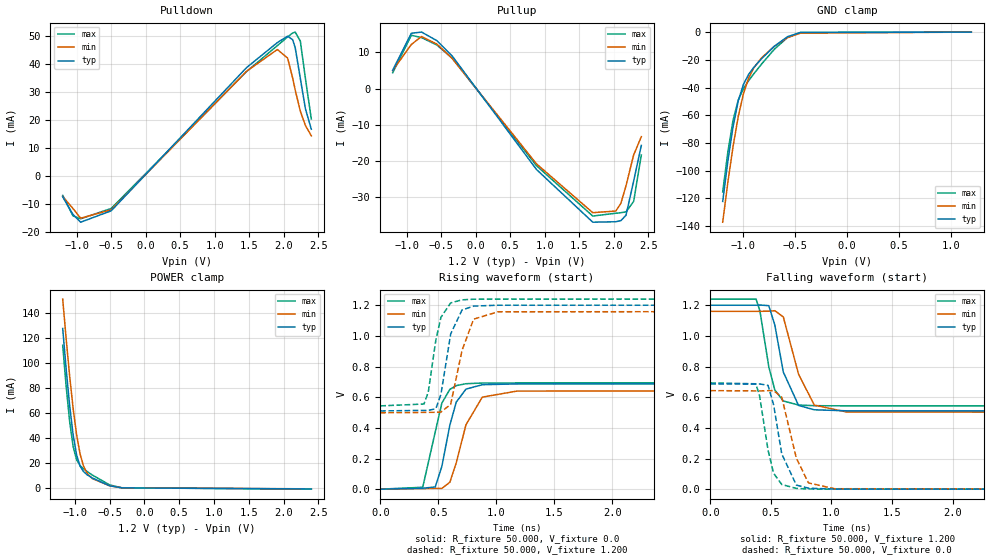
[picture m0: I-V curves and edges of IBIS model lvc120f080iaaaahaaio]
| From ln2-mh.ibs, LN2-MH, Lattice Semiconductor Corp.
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|   Model lvc120f080iaaaahaaio
[Model] lvc120f080iaaaahaaio
| Clamp models do not include dynamic input termination. Please refer to
| the lvc120axxxiaaaahaain model for input termination.
Model_type I/O
Polarity   Non-Inverting
Enable   Active-Low
Vinl =  0.420V
Vinh =  0.780V
Vmeas =  0.600V
Cref =  0.0F
Rref =  1.000M
Vref =  0.0V
C_comp   2.000pF   1.500pF   2.500pF
[Temperature Range]   25.000   0.125k   -40.000
[Voltage Range]   1.200V   1.160V   1.240V
[C Comp Corner]
C_comp   2.000pF   1.500pF   2.500pF
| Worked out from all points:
|   slope of the pulldown table from 0 to 0.18 V, typ, clamps not added: 37.3 ohm
|   slope of the pullup table from 0 to 0.18 V, typ, clamps not added: 37.3 ohm
|   GND clamp passes 1 mA (typ) near -0.50 V on its own axis
|   POWER clamp passes 1 mA (typ) near -0.44 V on its own axis
|   rising waveform, R_fixture 50.000, V_fixture 0.0: 20-80 % time 118ps typ, 146ps min, 108ps max; typ from 0 V to 0.687 V
|   rising waveform, R_fixture 50.000, V_fixture 1.200: 20-80 % time 93.6ps typ, 111ps min, 91.1ps max; typ from 0.51 V to 1.2 V
|   falling waveform, R_fixture 50.000, V_fixture 1.200: 20-80 % time 106ps typ, 140ps min, 93.7ps max; typ from 1.2 V to 0.51 V
|   falling waveform, R_fixture 50.000, V_fixture 0.0: 20-80 % time 95.5ps typ, 119ps min, 89.7ps max; typ from 0.687 V to 0 V
[Pulldown]
|Voltage   I(typ)   I(min)   I(max)
-1.2V     -7.568mA   -7.445mA   -7.032mA
-1.052V   -13.82mA   -11.7mA    -14.33mA
-941mV    -16.61mA   -15.19mA   -15.41mA
-497mV    -12.54mA   -12.17mA   -11.69mA
1.464V    38.62mA    37.31mA    37.21mA
1.908V    47.5mA     45.03mA    46.43mA
2.056V    49.79mA    42.01mA    49.53mA
2.13V     48.53mA    34.88mA    50.94mA
2.167V    45.68mA    30.56mA    51.26mA
2.241V    34.69mA    22.99mA    48.03mA
2.315V    23.84mA    17.89mA    34.64mA
2.4V      16.58mA    14.22mA    20.21mA
[Pullup]
|Voltage   I(typ)   I(min)   I(max)
-1.2V     5.079mA    5mA        4.396mA
-930mV    15.33mA    12.23mA    14.77mA
-782mV    15.65mA    14.42mA    14.12mA
-560mV    13.27mA    12.33mA    12.06mA
-338mV    9.007mA    8.333mA    8.416mA
883mV     -22.46mA   -20.89mA   -21.4mA
1.697V    -37.04mA   -34.4mA    -35.34mA
2.03V     -36.92mA   -33.95mA   -34.56mA
2.104V    -36.6mA    -31.81mA   -34.41mA
2.178V    -35.13mA   -26.97mA   -34.18mA
2.289V    -25.64mA   -18.41mA   -31.28mA
2.4V      -15.76mA   -13.34mA   -18.41mA
[GND_clamp]
|Voltage   I(typ)   I(min)   I(max)
-1.2V     -122.1mA   -137.1mA   -115.3mA
-1.15V    -92.88mA   -108.2mA   -86.34mA
-1.1V     -68.13mA   -82.44mA   -63.55mA
-1.05V    -49.58mA   -60.89mA   -48.98mA
-1V       -37.73mA   -44.48mA   -40.75mA
-950mV    -30.55mA   -33.19mA   -35.07mA
-900mV    -25.48mA   -25.79mA   -30.1mA
-825mV    -19.21mA   -18.55mA   -23.07mA
-700mV    -10.12mA   -10.12mA   -12.27mA
-575mV    -3.338mA   -4.053mA   -3.949mA
-450mV    -310.5uA   -787.2uA   -256.6uA
1.2V      0A         0A         0A
[POWER_clamp]
|Voltage   I(typ)   I(min)   I(max)
-1.175V   127.9mA    151.5mA    114.4mA
-1.125V   95.11mA    119.3mA    81.3mA
-1.075V   66.05mA    89.76mA    53.26mA
-1.025V   42.55mA    63.81mA    33.28mA
-975mV    26.45mA    42.66mA    22.68mA
-925mV    17.56mA    27.27mA    18.01mA
-875mV    13.18mA    17.5mA     15.4mA
-825mV    10.7mA     11.9mA     13.32mA
-750mV    8.076mA    7.611mA    10.45mA
-500mV    1.821mA    1.817mA    2.516mA
-325mV    164.5uA    258.7uA    189uA
2.4V      -731uA     -642.7uA   -887.3uA
[Ramp]
| variable   typ   min   max
dV/dt_r   0.412/0.118n   0.386/0.146n   0.416/0.108n
dV/dt_f   0.414/0.106n   0.397/0.140n   0.418/93.724p
R_load = 50.000
[Rising Waveform]
R_fixture= 50.000
V_fixture= 0.0
V_fixture_min= 0.0
V_fixture_max= 0.0
|time   V(typ)   V(min)   V(max)
0s        1.143uV    6.223uV    521.7nV
366ps     6.154mV    3.58mV     12.35mV
474ps     14.41mV    5.49mV     373.5mV
531ps     148.7mV    4.902mV    561.6mV
600ps     418.3mV    45.12mV    651.1mV
655ps     567.9mV    171.9mV    675.4mV
739ps     652.6mV    420.5mV    687.9mV
880ps     681.4mV    600.4mV    692.2mV
1.179ns   686.6mV    639.9mV    692.9mV
10ns      686.9mV    642.6mV    693.1mV
[Rising Waveform]
R_fixture= 50.000
V_fixture= 1.200
V_fixture_min= 1.160
V_fixture_max= 1.240
|time   V(typ)   V(min)   V(max)
0s        510.2mV    498.2mV    543.2mV
377ps     513.9mV    500.6mV    555.4mV
414ps     513.9mV    501.2mV    633.5mV
479ps     524.6mV    501.3mV    972.3mV
523ps     618.3mV    502.7mV    1.121V
607ps     1.012V     553mV      1.215V
705ps     1.169V     905.9mV    1.235V
805ps     1.194V     1.109V     1.239V
1.015ns   1.2V       1.157V     1.24V
10ns      1.2V       1.16V      1.24V
[Falling Waveform]
R_fixture= 50.000
V_fixture= 1.200
V_fixture_min= 1.160
V_fixture_max= 1.240
|time   V(typ)   V(min)   V(max)
0s        1.2V       1.16V      1.24V
378ps     1.2V       1.16V      1.24V
410ps     1.201V     1.16V      1.162V
483ps     1.197V     1.161V     799.2mV
533ps     1.071V     1.164V     646.6mV
603ps     764mV      1.123V     575.3mV
729ps     546.1mV    749.6mV    548.8mV
859ps     517.7mV    548.3mV    544.5mV
1.129ns   511mV      503mV      543.4mV
10ns      510.2mV    498.2mV    543.2mV
[Falling Waveform]
R_fixture= 50.000
V_fixture= 0.0
V_fixture_min= 0.0
V_fixture_max= 0.0
|time   V(typ)   V(min)   V(max)
0s        686.8mV    642.6mV    693mV
376ps     685.1mV    641.1mV    687.4mV
407ps     686.3mV    640.9mV    608.8mV
477ps     677.3mV    642.2mV    254.4mV
523ps     549.9mV    643mV      103.5mV
590ps     230.2mV    600.1mV    30.57mV
711ps     26.5mV     201mV      4.779mV
811ps     6.404mV    40.89mV    1.254mV
1.026ns   599.4uV    2.814mV    141.9uV
10ns      1.156uV    6.238uV    534.4nV
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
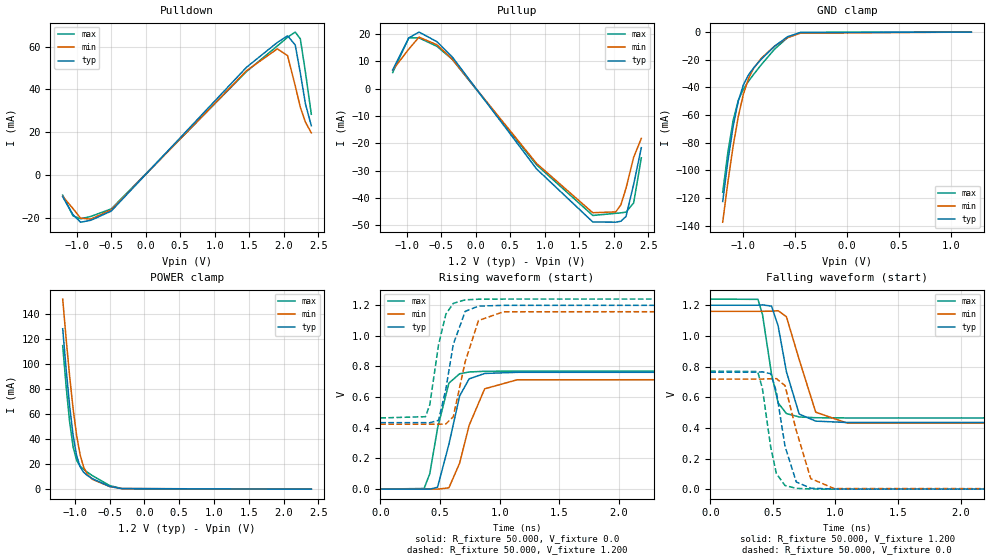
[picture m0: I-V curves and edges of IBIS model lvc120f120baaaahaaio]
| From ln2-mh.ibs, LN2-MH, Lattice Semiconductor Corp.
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|   Model lvc120f120baaaahaaio
[Model] lvc120f120baaaahaaio
| Clamp models do not include dynamic input termination. Please refer to
| the lvc120axxxbaaaahaain model for input termination.
Model_type I/O
Polarity   Non-Inverting
Enable   Active-Low
Vinl =  0.420V
Vinh =  0.780V
Vmeas =  0.600V
Cref =  0.0F
Rref =  1.000M
Vref =  0.0V
C_comp   2.000pF   1.500pF   2.500pF
[Temperature Range]   25.000   0.125k   -40.000
[Voltage Range]   1.200V   1.160V   1.240V
[C Comp Corner]
C_comp   2.000pF   1.500pF   2.500pF
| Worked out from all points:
|   slope of the pulldown table from 0 to 0.18 V, typ, clamps not added: 28.2 ohm
|   slope of the pullup table from 0 to 0.18 V, typ, clamps not added: 28.8 ohm
|   GND clamp passes 1 mA (typ) near -0.50 V on its own axis
|   POWER clamp passes 1 mA (typ) near -0.43 V on its own axis
|   rising waveform, R_fixture 50.000, V_fixture 0.0: 20-80 % time 125ps typ, 154ps min, 110ps max; typ from 0 V to 0.763 V
|   rising waveform, R_fixture 50.000, V_fixture 1.200: 20-80 % time 107ps typ, 124ps min, 99.1ps max; typ from 0.433 V to 1.2 V
|   falling waveform, R_fixture 50.000, V_fixture 1.200: 20-80 % time 107ps typ, 140ps min, 92.2ps max; typ from 1.2 V to 0.433 V
|   falling waveform, R_fixture 50.000, V_fixture 0.0: 20-80 % time 95.9ps typ, 122ps min, 85.3ps max; typ from 0.763 V to 0 V
[Pulldown]
|Voltage   I(typ)   I(min)   I(max)
-1.2V     -10.29mA   -10.11mA   -9.541mA
-1.052V   -18.64mA   -15.78mA   -19.21mA
-941mV    -22.19mA   -20.32mA   -20.6mA
-793mV    -21.3mA    -20.74mA   -19.49mA
-497mV    -16.98mA   -16.39mA   -15.97mA
1.464V    50.41mA    48.78mA    48.4mA
1.908V    61.95mA    58.96mA    60.32mA
2.056V    65.05mA    55.78mA    64.38mA
2.167V    60.79mA    41.65mA    66.8mA
2.241V    47.61mA    31.59mA    63.62mA
2.315V    33.16mA    24.63mA    47.99mA
2.4V      22.96mA    19.61mA    28.32mA
[Pullup]
|Voltage   I(typ)   I(min)   I(max)
-1.2V     6.849mA    6.78mA     5.874mA
-967mV    18.55mA    14.45mA    18.59mA
-819mV    20.67mA    18.83mA    18.55mA
-560mV    17.17mA    16.04mA    15.46mA
-338mV    11.58mA    10.78mA    10.71mA
883mV     -29.4mA    -27.4mA    -27.91mA
1.697V    -48.81mA   -45.43mA   -46.43mA
2.03V     -48.89mA   -45.12mA   -45.65mA
2.104V    -48.53mA   -42.54mA   -45.47mA
2.178V    -46.81mA   -36.5mA    -45.2mA
2.289V    -35.05mA   -25.15mA   -41.82mA
2.4V      -21.63mA   -18.24mA   -25.35mA
[GND_clamp]
|Voltage   I(typ)   I(min)   I(max)
-1.2V     -122.6mA   -137.6mA   -116mA
-1.15V    -93.41mA   -108.6mA   -87.01mA
-1.1V     -68.62mA   -82.86mA   -64.16mA
-1.05V    -50.02mA   -61.28mA   -49.51mA
-1V       -38.12mA   -44.82mA   -41.23mA
-950mV    -30.88mA   -33.5mA    -35.49mA
-900mV    -25.78mA   -26.06mA   -30.47mA
-825mV    -19.44mA   -18.76mA   -23.36mA
-700mV    -10.25mA   -10.24mA   -12.44mA
-575mV    -3.381mA   -4.102mA   -4.007mA
-450mV    -315.1uA   -796.4uA   -262uA
1.2V      0A         0A         0A
[POWER_clamp]
|Voltage   I(typ)   I(min)   I(max)
-1.175V   127.9mA    151.6mA    114.4mA
-1.125V   95.2mA     119.4mA    81.41mA
-1.075V   66.17mA    89.85mA    53.4mA
-1.025V   42.7mA     63.91mA    33.48mA
-975mV    26.64mA    42.78mA    22.93mA
-925mV    17.79mA    27.41mA    18.29mA
-875mV    13.42mA    17.66mA    15.69mA
-825mV    10.95mA    12.07mA    13.61mA
-750mV    8.323mA    7.791mA    10.74mA
-500mV    2.04mA     1.98mA     2.782mA
-325mV    310.3uA    373.2uA    366.8uA
2.4V      -105uA     -106.2uA   -106.1uA
[Ramp]
| variable   typ   min   max
dV/dt_r   0.458/0.125n   0.431/0.154n   0.462/0.110n
dV/dt_f   0.460/0.107n   0.442/0.141n   0.466/92.084p
R_load = 50.000
[Rising Waveform]
R_fixture= 50.000
V_fixture= 0.0
V_fixture_min= 0.0
V_fixture_max= 0.0
|time   V(typ)   V(min)   V(max)
0s        932.8nV    5.117uV    427.9nV
367ps     63.02uV    37.84uV    3.772mV
415ps     -600.1uV   68.02uV    100.4mV
480ps     11.92mV    -454.5uV   397mV
575ps     291.8mV    7.772mV    691.2mV
665ps     607.8mV    169.1mV    752.4mV
745ps     719.3mV    416.5mV    764.3mV
875ps     754.5mV    654.3mV    768.7mV
1.146ns   762mV      712.9mV    769.6mV
10ns      762.5mV    717.9mV    769.8mV
[Rising Waveform]
R_fixture= 50.000
V_fixture= 1.200
V_fixture_min= 1.160
V_fixture_max= 1.240
|time   V(typ)   V(min)   V(max)
0s        433.4mV    423.4mV    464.1mV
379ps     433.3mV    423.4mV    472.4mV
415ps     432.9mV    423.4mV    550.5mV
488ps     448.4mV    423mV      940.7mV
550ps     654.4mV    425.1mV    1.142V
612ps     944.9mV    472.7mV    1.212V
712ps     1.16V      832mV      1.235V
823ps     1.194V     1.1V       1.239V
1.033ns   1.199V     1.157V     1.24V
10ns      1.2V       1.16V      1.24V
[Falling Waveform]
R_fixture= 50.000
V_fixture= 1.200
V_fixture_min= 1.160
V_fixture_max= 1.240
|time   V(typ)   V(min)   V(max)
0s        1.2V       1.16V      1.24V
381ps     1.2V       1.16V      1.238V
417ps     1.202V     1.16V      1.139V
489ps     1.194V     1.161V     751.3mV
542ps     1.065V     1.164V     562.5mV
608ps     766mV      1.125V     493.3mV
710ps     490mV      845.3mV    471mV
842ps     443.8mV    502.2mV    466mV
1.092ns   434.9mV    431.3mV    464.5mV
10ns      433.4mV    423.4mV    464.1mV
[Falling Waveform]
R_fixture= 50.000
V_fixture= 0.0
V_fixture_min= 0.0
V_fixture_max= 0.0
|time   V(typ)   V(min)   V(max)
0s        762.5mV    717.8mV    769.7mV
378ps     763.1mV    717.9mV    767.5mV
416ps     765.2mV    718.2mV    658mV
483ps     753mV      720.2mV    272mV
528ps     635.2mV    721.1mV    101.4mV
597ps     279.4mV    675.6mV    23.77mV
687ps     46.61mV    381.9mV    5.309mV
802ps     6.562mV    69.15mV    1.132mV
989ps     837.8uV    4.043mV    192uV
10ns      942.7nV    5.124uV    437.8nV
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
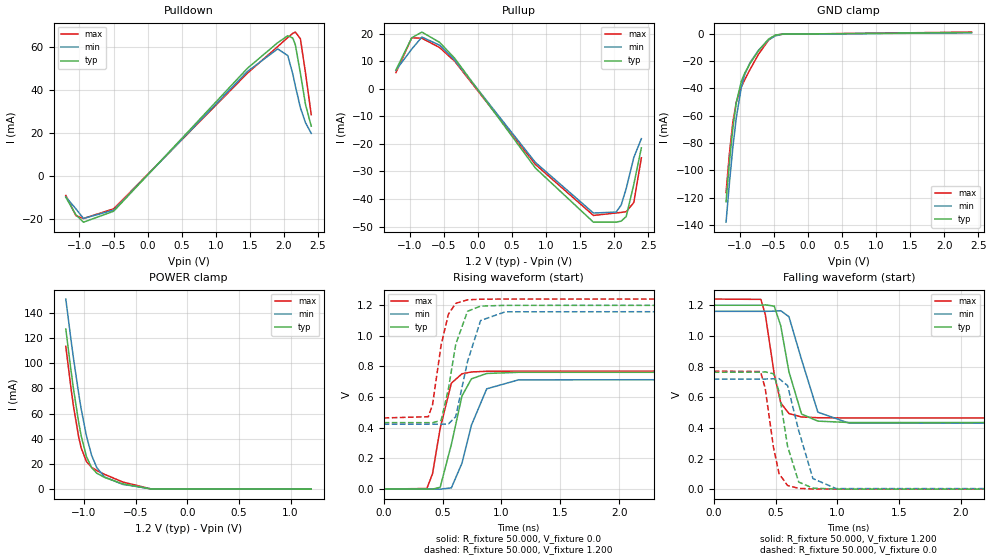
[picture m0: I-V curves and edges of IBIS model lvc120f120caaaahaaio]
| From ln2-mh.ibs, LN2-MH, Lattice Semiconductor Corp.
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|   Model lvc120f120caaaahaaio
[Model] lvc120f120caaaahaaio
| Clamp models do not include dynamic input termination. Please refer to
| the lvc120axxxcaaaahaain model for input termination.
Model_type I/O
Polarity   Non-Inverting
Enable   Active-Low
Vinl =  0.420V
Vinh =  0.780V
Vmeas =  0.600V
Cref =  0.0F
Rref =  1.000M
Vref =  0.0V
C_comp   2.000pF   1.500pF   2.500pF
[Temperature Range]   25.000   0.125k   -40.000
[Voltage Range]   1.200V   1.160V   1.240V
[C Comp Corner]
C_comp   2.000pF   1.500pF   2.500pF
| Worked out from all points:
|   slope of the pulldown table from 0 to 0.18 V, typ, clamps not added: 29 ohm
|   slope of the pullup table from 0 to 0.18 V, typ, clamps not added: 28.5 ohm
|   GND clamp passes 1 mA (typ) near -0.47 V on its own axis
|   POWER clamp passes 1 mA (typ) near -0.46 V on its own axis
|   rising waveform, R_fixture 50.000, V_fixture 0.0: 20-80 % time 125ps typ, 154ps min, 110ps max; typ from 0 V to 0.763 V
|   rising waveform, R_fixture 50.000, V_fixture 1.200: 20-80 % time 107ps typ, 124ps min, 99.1ps max; typ from 0.433 V to 1.2 V
|   falling waveform, R_fixture 50.000, V_fixture 1.200: 20-80 % time 107ps typ, 140ps min, 92.2ps max; typ from 1.2 V to 0.433 V
|   falling waveform, R_fixture 50.000, V_fixture 0.0: 20-80 % time 95.9ps typ, 122ps min, 85.3ps max; typ from 0.763 V to 0 V
[Pulldown]
|Voltage   I(typ)   I(min)   I(max)
-1.2V     -10.07mA   -9.929mA   -9.28mA
-1.052V   -18.25mA   -15.5mA    -18.68mA
-941mV    -21.7mA    -19.95mA   -19.98mA
-497mV    -16.58mA   -16.07mA   -15.47mA
1.464V    49.89mA    48.41mA    47.61mA
1.908V    61.8mA     58.9mA     59.98mA
2.056V    65.03mA    55.79mA    64.2mA
2.13V     63.95mA    47.18mA    66.15mA
2.167V    60.82mA    41.66mA    66.73mA
2.241V    47.64mA    31.6mA     63.61mA
2.315V    33.19mA    24.64mA    47.99mA
2.4V      22.98mA    19.62mA    28.33mA
[Pullup]
|Voltage   I(typ)   I(min)   I(max)
-1.2V     6.872mA    6.794mA    5.884mA
-967mV    18.58mA    14.47mA    18.56mA
-819mV    20.62mA    18.82mA    18.38mA
-560mV    16.9mA     15.86mA    15.02mA
-338mV    11.11mA    10.43mA    10.03mA
846mV     -28.75mA   -26.73mA   -27.43mA
1.697V    -48.41mA   -45.09mA   -45.96mA
2.03V     -48.39mA   -44.73mA   -45.05mA
2.104V    -48.03mA   -42.18mA   -44.86mA
2.178V    -46.34mA   -36.19mA   -44.58mA
2.289V    -34.72mA   -24.93mA   -41.28mA
2.4V      -21.42mA   -18.08mA   -25.04mA
[GND_clamp]
|Voltage   I(typ)   I(min)   I(max)
-1.2V     -123mA     -137.9mA   -116.3mA
-1.15V    -93.77mA   -109mA     -87.45mA
-1.1V     -69.04mA   -83.2mA    -64.7mA
-1.05V    -50.52mA   -61.66mA   -50.16mA
-975mV    -34.68mA   -39.02mA   -38.92mA
-925mV    -28.78mA   -29.88mA   -33.66mA
-850mV    -22.06mA   -21.38mA   -26.4mA
-725mV    -12.54mA   -12.25mA   -15.19mA
-575mV    -3.931mA   -4.562mA   -4.668mA
-475mV    -1.083mA   -1.617mA   -1.164mA
-375mV    -415.4uA   -497uA     -482.7uA
2.4V      768.5uA    596.7uA    1.09mA
[POWER_clamp]
|Voltage   I(typ)   I(min)   I(max)
-1.175V   127.2mA    151mA      113.4mA
-1.125V   94.42mA    118.8mA    80.34mA
-1.1V     79.34mA    103.6mA    65.54mA
-1.05V    52.82mA    75.75mA    41.2mA
-1.025V   41.91mA    63.3mA     32.44mA
-975mV    25.85mA    42.18mA    21.92mA
-925mV    17.02mA    26.81mA    17.31mA
-875mV    12.68mA    17.07mA    14.77mA
-800mV    9.315mA    9.719mA    11.8mA
-625mV    4.252mA    3.803mA    5.726mA
-350mV    125.8uA    261.6uA    148.8uA
1.2V      0A         0A         0A
[Ramp]
| variable   typ   min   max
dV/dt_r   0.458/0.125n   0.431/0.154n   0.462/0.110n
dV/dt_f   0.460/0.107n   0.442/0.141n   0.466/92.084p
R_load = 50.000
[Rising Waveform]
R_fixture= 50.000
V_fixture= 0.0
V_fixture_min= 0.0
V_fixture_max= 0.0
|time   V(typ)   V(min)   V(max)
0s        932.8nV    5.117uV    427.9nV
367ps     63.02uV    37.84uV    3.772mV
415ps     -600.1uV   68.02uV    100.4mV
480ps     11.92mV    -454.5uV   397mV
575ps     291.8mV    7.772mV    691.2mV
665ps     607.8mV    169.1mV    752.4mV
745ps     719.3mV    416.5mV    764.3mV
875ps     754.5mV    654.3mV    768.7mV
1.146ns   762mV      712.9mV    769.6mV
10ns      762.5mV    717.9mV    769.8mV
[Rising Waveform]
R_fixture= 50.000
V_fixture= 1.200
V_fixture_min= 1.160
V_fixture_max= 1.240
|time   V(typ)   V(min)   V(max)
0s        433.4mV    423.4mV    464.1mV
379ps     433.3mV    423.4mV    472.4mV
415ps     432.9mV    423.4mV    550.5mV
488ps     448.4mV    423mV      940.7mV
550ps     654.4mV    425.1mV    1.142V
612ps     944.9mV    472.7mV    1.212V
712ps     1.16V      832mV      1.235V
823ps     1.194V     1.1V       1.239V
1.033ns   1.199V     1.157V     1.24V
10ns      1.2V       1.16V      1.24V
[Falling Waveform]
R_fixture= 50.000
V_fixture= 1.200
V_fixture_min= 1.160
V_fixture_max= 1.240
|time   V(typ)   V(min)   V(max)
0s        1.2V       1.16V      1.24V
381ps     1.2V       1.16V      1.238V
417ps     1.202V     1.16V      1.139V
489ps     1.194V     1.161V     751.3mV
542ps     1.065V     1.164V     562.5mV
608ps     766mV      1.125V     493.3mV
710ps     490mV      845.3mV    471mV
842ps     443.8mV    502.2mV    466mV
1.092ns   434.9mV    431.3mV    464.5mV
10ns      433.4mV    423.4mV    464.1mV
[Falling Waveform]
R_fixture= 50.000
V_fixture= 0.0
V_fixture_min= 0.0
V_fixture_max= 0.0
|time   V(typ)   V(min)   V(max)
0s        762.5mV    717.8mV    769.7mV
378ps     763.1mV    717.9mV    767.5mV
416ps     765.2mV    718.2mV    658mV
483ps     753mV      720.2mV    272mV
528ps     635.2mV    721.1mV    101.4mV
597ps     279.4mV    675.6mV    23.77mV
687ps     46.61mV    381.9mV    5.309mV
802ps     6.562mV    69.15mV    1.132mV
989ps     837.8uV    4.043mV    192uV
10ns      942.7nV    5.124uV    437.8nV
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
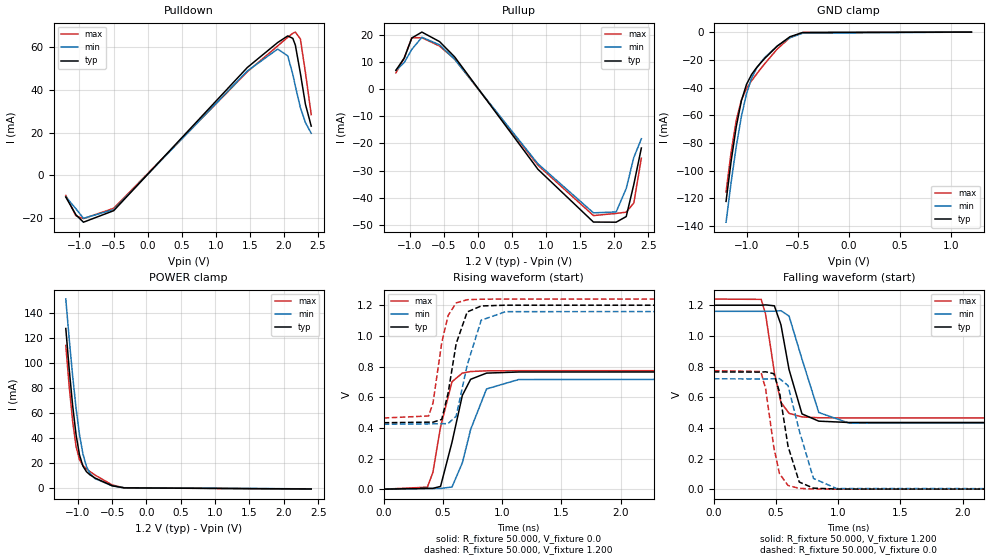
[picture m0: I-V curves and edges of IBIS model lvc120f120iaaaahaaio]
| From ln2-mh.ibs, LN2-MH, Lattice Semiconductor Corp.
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|   Model lvc120f120iaaaahaaio
[Model] lvc120f120iaaaahaaio
| Clamp models do not include dynamic input termination. Please refer to
| the lvc120axxxiaaaahaain model for input termination.
Model_type I/O
Polarity   Non-Inverting
Enable   Active-Low
Vinl =  0.420V
Vinh =  0.780V
Vmeas =  0.600V
Cref =  0.0F
Rref =  1.000M
Vref =  0.0V
C_comp   2.000pF   1.500pF   2.500pF
[Temperature Range]   25.000   0.125k   -40.000
[Voltage Range]   1.200V   1.160V   1.240V
[C Comp Corner]
C_comp   2.000pF   1.500pF   2.500pF
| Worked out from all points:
|   slope of the pulldown table from 0 to 0.18 V, typ, clamps not added: 28.4 ohm
|   slope of the pullup table from 0 to 0.18 V, typ, clamps not added: 28.5 ohm
|   GND clamp passes 1 mA (typ) near -0.50 V on its own axis
|   POWER clamp passes 1 mA (typ) near -0.44 V on its own axis
|   rising waveform, R_fixture 50.000, V_fixture 0.0: 20-80 % time 125ps typ, 153ps min, 110ps max; typ from 0 V to 0.765 V
|   rising waveform, R_fixture 50.000, V_fixture 1.200: 20-80 % time 107ps typ, 124ps min, 98.5ps max; typ from 0.433 V to 1.2 V
|   falling waveform, R_fixture 50.000, V_fixture 1.200: 20-80 % time 107ps typ, 141ps min, 92.1ps max; typ from 1.2 V to 0.433 V
|   falling waveform, R_fixture 50.000, V_fixture 0.0: 20-80 % time 96.1ps typ, 122ps min, 85.5ps max; typ from 0.765 V to 0 V
[Pulldown]
|Voltage   I(typ)   I(min)   I(max)
-1.2V     -10.22mA   -10.05mA   -9.458mA
-1.052V   -18.5mA    -15.68mA   -19.01mA
-941mV    -21.98mA   -20.16mA   -20.31mA
-497mV    -16.58mA   -16.07mA   -15.45mA
1.464V    50.53mA    48.89mA    48.52mA
1.908V    62.19mA    59.14mA    60.61mA
2.056V    65.29mA    55.93mA    64.67mA
2.13V     64.14mA    47.28mA    66.54mA
2.167V    60.99mA    41.75mA    67.08mA
2.241V    47.75mA    31.67mA    63.85mA
2.315V    33.26mA    24.69mA    48.13mA
2.4V      23.03mA    19.66mA    28.41mA
[Pullup]
|Voltage   I(typ)   I(min)   I(max)
-1.2V     6.935mA    6.851mA    5.966mA
-1.078V   11.4mA     9.771mA    11.47mA
-967mV    18.79mA    14.6mA     18.9mA
-819mV    20.96mA    19.05mA    18.9mA
-560mV    17.46mA    16.27mA    15.82mA
-338mV    11.82mA    10.96mA    11mA
883mV     -29.49mA   -27.49mA   -27.99mA
1.697V    -48.89mA   -45.5mA    -46.51mA
2.03V     -48.94mA   -45.18mA   -45.71mA
2.178V    -46.87mA   -36.54mA   -45.26mA
2.289V    -35.11mA   -25.18mA   -41.89mA
2.4V      -21.66mA   -18.26mA   -25.4mA
[GND_clamp]
|Voltage   I(typ)   I(min)   I(max)
-1.2V     -122.1mA   -137.1mA   -115.3mA
-1.15V    -92.88mA   -108.2mA   -86.34mA
-1.1V     -68.13mA   -82.44mA   -63.55mA
-1.05V    -49.58mA   -60.89mA   -48.98mA
-1V       -37.73mA   -44.48mA   -40.75mA
-950mV    -30.55mA   -33.19mA   -35.07mA
-900mV    -25.48mA   -25.79mA   -30.1mA
-825mV    -19.21mA   -18.55mA   -23.07mA
-700mV    -10.12mA   -10.12mA   -12.27mA
-575mV    -3.338mA   -4.053mA   -3.949mA
-450mV    -310.5uA   -787.2uA   -256.6uA
1.2V      0A         0A         0A
[POWER_clamp]
|Voltage   I(typ)   I(min)   I(max)
-1.175V   127.9mA    151.5mA    114.4mA
-1.125V   95.11mA    119.3mA    81.3mA
-1.075V   66.05mA    89.76mA    53.26mA
-1.025V   42.55mA    63.81mA    33.28mA
-975mV    26.45mA    42.66mA    22.68mA
-925mV    17.56mA    27.27mA    18.01mA
-875mV    13.18mA    17.5mA     15.4mA
-825mV    10.7mA     11.9mA     13.32mA
-750mV    8.076mA    7.611mA    10.45mA
-500mV    1.821mA    1.817mA    2.516mA
-325mV    164.5uA    258.7uA    189uA
2.4V      -731uA     -642.7uA   -887.3uA
[Ramp]
| variable   typ   min   max
dV/dt_r   0.459/0.125n   0.432/0.154n   0.464/0.110n
dV/dt_f   0.460/0.107n   0.442/0.141n   0.466/92.070p
R_load = 50.000
[Rising Waveform]
R_fixture= 50.000
V_fixture= 0.0
V_fixture_min= 0.0
V_fixture_max= 0.0
|time   V(typ)   V(min)   V(max)
0s        932.8nV    5.117uV    427.9nV
369ps     5.457mV    3.359mV    13.11mV
415ps     5.311mV    4.45mV     108.1mV
480ps     17.93mV    4.6mV      405.9mV
577ps     306.9mV    14.41mV    701mV
664ps     611.9mV    172mV      757.1mV
734ps     716.7mV    389.5mV    767.4mV
868ps     757mV      653.7mV    771.8mV
1.139ns   764.3mV    715.1mV    772.7mV
10ns      764.8mV    720mV      772.9mV
[Rising Waveform]
R_fixture= 50.000
V_fixture= 1.200
V_fixture_min= 1.160
V_fixture_max= 1.240
|time   V(typ)   V(min)   V(max)
0s        433.4mV    423.4mV    464.1mV
379ps     437mV      425.8mV    477.5mV
416ps     436.8mV    426.3mV    560.3mV
490ps     454.8mV    426.3mV    954.9mV
544ps     627.1mV    428mV      1.133V
612ps     949.6mV    476.4mV    1.215V
705ps     1.156V     809.6mV    1.236V
823ps     1.195V     1.102V     1.239V
1.03ns    1.2V       1.158V     1.24V
10ns      1.2V       1.16V      1.24V
[Falling Waveform]
R_fixture= 50.000
V_fixture= 1.200
V_fixture_min= 1.160
V_fixture_max= 1.240
|time   V(typ)   V(min)   V(max)
0s        1.2V       1.16V      1.24V
381ps     1.2V       1.16V      1.238V
416ps     1.202V     1.16V      1.143V
487ps     1.196V     1.161V     761.4mV
540ps     1.072V     1.164V     566.5mV
605ps     780.2mV    1.129V     494.8mV
709ps     490.9mV    848.6mV    471.1mV
844ps     443.6mV    500mV      465.9mV
1.085ns   435mV      431.6mV    464.5mV
10ns      433.4mV    423.4mV    464.1mV
[Falling Waveform]
R_fixture= 50.000
V_fixture= 0.0
V_fixture_min= 0.0
V_fixture_max= 0.0
|time   V(typ)   V(min)   V(max)
0s        764.8mV    720mV      772.8mV
378ps     763.6mV    718.8mV    767.7mV
417ps     765.6mV    718.8mV    653.3mV
483ps     753.1mV    720.5mV    271.8mV
528ps     635.1mV    721.2mV    101.3mV
597ps     279.1mV    675.7mV    23.76mV
687ps     46.58mV    381.8mV    5.308mV
801ps     6.651mV    70.34mV    1.146mV
987ps     852.5uV    4.128mV    194.6uV
10ns      942.7nV    5.125uV    437.9nV
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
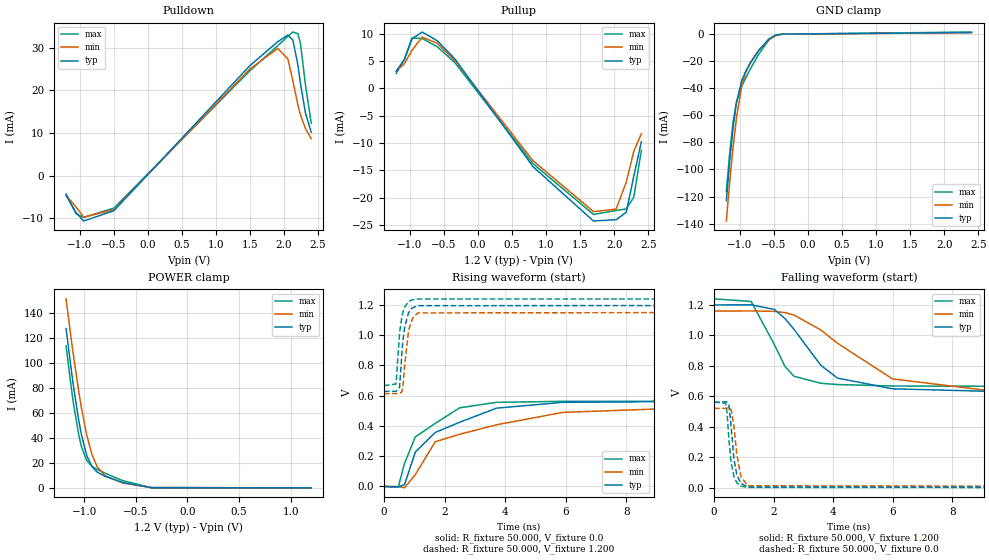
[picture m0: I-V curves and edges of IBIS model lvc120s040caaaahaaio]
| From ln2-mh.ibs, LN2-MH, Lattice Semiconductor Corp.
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|   Model lvc120s040caaaahaaio
[Model] lvc120s040caaaahaaio
| Clamp models do not include dynamic input termination. Please refer to
| the lvc120axxxcaaaahaain model for input termination.
Model_type I/O
Polarity   Non-Inverting
Enable   Active-Low
Vinl =  0.420V
Vinh =  0.780V
Vmeas =  0.600V
Cref =  0.0F
Rref =  1.000M
Vref =  0.0V
C_comp   2.000pF   1.500pF   2.500pF
[Temperature Range]   25.000   0.125k   -40.000
[Voltage Range]   1.200V   1.160V   1.240V
[C Comp Corner]
C_comp   2.000pF   1.500pF   2.500pF
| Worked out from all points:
|   slope of the pulldown table from 0 to 0.18 V, typ, clamps not added: 58 ohm
|   slope of the pullup table from 0 to 0.18 V, typ, clamps not added: 55.7 ohm
|   GND clamp passes 1 mA (typ) near -0.47 V on its own axis
|   POWER clamp passes 1 mA (typ) near -0.46 V on its own axis
|   rising waveform, R_fixture 50.000, V_fixture 0.0: 20-80 % time 1.9ns typ, 2.8ns min, 1.26ns max; typ from 0 V to 0.562 V
|   rising waveform, R_fixture 50.000, V_fixture 1.200: 20-80 % time 165ps typ, 181ps min, 157ps max; typ from 0.629 V to 1.2 V
|   falling waveform, R_fixture 50.000, V_fixture 1.200: 20-80 % time 1.44ns typ, 2.4ns min, 837ps max; typ from 1.2 V to 0.629 V
|   falling waveform, R_fixture 50.000, V_fixture 0.0: 20-80 % time 175ps typ, 198ps min, 164ps max; typ from 0.562 V to 0 V
[Pulldown]
|Voltage   I(typ)   I(min)   I(max)
-1.2V     -4.694mA   -4.636mA   -4.325mA
-1.052V   -8.754mA   -7.419mA   -9.038mA
-941mV    -10.7mA    -9.794mA   -9.848mA
-497mV    -8.256mA   -8.027mA   -7.655mA
1.501V    25.87mA    25.07mA    24.68mA
1.908V    31.45mA    29.88mA    30.51mA
2.056V    33.03mA    27.43mA    32.75mA
2.13V     31.89mA    22.27mA    33.74mA
2.204V    25.99mA    16.6mA     33.34mA
2.241V    21.71mA    14.32mA    31.14mA
2.315V    14.69mA    11.03mA    21.34mA
2.4V      10.14mA    8.66mA     12.29mA
[Pullup]
|Voltage   I(typ)   I(min)   I(max)
-1.2V     3.124mA    3.061mA    2.691mA
-1.078V   5.308mA    4.516mA    5.332mA
-967mV    9.069mA    6.961mA    9.159mA
-819mV    10.27mA    9.343mA    9.088mA
-597mV    8.674mA    8.198mA    7.579mA
-338mV    5.347mA    5.06mA     4.671mA
809mV     -14.35mA   -13.26mA   -13.8mA
1.697V    -24.28mA   -22.57mA   -23.08mA
2.03V     -24.03mA   -22.1mA    -22.35mA
2.178V    -22.69mA   -17.18mA   -22.08mA
2.289V    -16.07mA   -11.54mA   -19.91mA
2.4V      -9.782mA   -8.301mA   -11.34mA
[GND_clamp]
|Voltage   I(typ)   I(min)   I(max)
-1.2V     -123mA     -137.9mA   -116.3mA
-1.15V    -93.77mA   -109mA     -87.45mA
-1.1V     -69.04mA   -83.2mA    -64.7mA
-1.05V    -50.52mA   -61.66mA   -50.16mA
-975mV    -34.68mA   -39.02mA   -38.92mA
-925mV    -28.78mA   -29.88mA   -33.66mA
-850mV    -22.06mA   -21.38mA   -26.4mA
-725mV    -12.54mA   -12.25mA   -15.19mA
-575mV    -3.931mA   -4.562mA   -4.668mA
-475mV    -1.083mA   -1.617mA   -1.164mA
-375mV    -415.4uA   -497uA     -482.7uA
2.4V      768.5uA    596.7uA    1.09mA
[POWER_clamp]
|Voltage   I(typ)   I(min)   I(max)
-1.175V   127.2mA    151mA      113.4mA
-1.125V   94.42mA    118.8mA    80.34mA
-1.1V     79.34mA    103.6mA    65.54mA
-1.05V    52.82mA    75.75mA    41.2mA
-1.025V   41.91mA    63.3mA     32.44mA
-975mV    25.85mA    42.18mA    21.92mA
-925mV    17.02mA    26.81mA    17.31mA
-875mV    12.68mA    17.07mA    14.77mA
-800mV    9.315mA    9.719mA    11.8mA
-625mV    4.252mA    3.803mA    5.726mA
-350mV    125.8uA    261.6uA    148.8uA
1.2V      0A         0A         0A
[Ramp]
| variable   typ   min   max
dV/dt_r   0.337/1.899n   0.313/2.799n   0.338/1.264n
dV/dt_f   0.343/1.444n   0.328/2.401n   0.344/0.837n
R_load = 50.000
[Rising Waveform]
R_fixture= 50.000
V_fixture= 0.0
V_fixture_min= 0.0
V_fixture_max= 0.0
|time   V(typ)   V(min)   V(max)
0s        1.465uV    7.911uV    665.2nV
471ps     -2.669mV   -246.3uV   -4.958mV
678ps     11.81mV    -9.037mV   152.9mV
1.035ns   227.6mV    78.7mV     327.7mV
1.692ns   357.2mV    295.9mV    417.1mV
2.501ns   424.8mV    345.3mV    520.1mV
3.716ns   517.8mV    407.8mV    556.1mV
5.902ns   556.1mV    489.7mV    562.8mV
9.832ns   561.8mV    518.2mV    563.3mV
50ns      562.1mV    521.7mV    563.3mV
[Rising Waveform]
R_fixture= 50.000
V_fixture= 1.200
V_fixture_min= 1.160
V_fixture_max= 1.240
|time   V(typ)   V(min)   V(max)
0s        629.1mV    613.5mV    666.1mV
399ps     628.7mV    613.6mV    677.6mV
516ps     656.2mV    613.6mV    1.015V
590ps     879.3mV    626.3mV    1.121V
629ps     969.9mV    665.1mV    1.155V
683ps     1.053V     799.9mV    1.186V
812ps     1.149V     1.03V      1.222V
932ps     1.18V      1.108V     1.234V
1.112ns   1.195V     1.147V     1.239V
50ns      1.2V       1.16V      1.24V
[Falling Waveform]
R_fixture= 50.000
V_fixture= 1.200
V_fixture_min= 1.160
V_fixture_max= 1.240
|time   V(typ)   V(min)   V(max)
0s        1.2V       1.16V      1.24V
1.246ns   1.201V     1.161V     1.223V
2.026ns   1.171V     1.158V     940.1mV
2.382ns   1.111V     1.15V      796.7mV
2.687ns   1.04V      1.134V     732mV
3.586ns   804.1mV    1.036V     686.3mV
4.146ns   720.3mV    948.9mV    677.8mV
5.996ns   649.9mV    715mV      668.4mV
9.492ns   631.8mV    631.7mV    666.3mV
50ns      629mV      613.5mV    666.1mV
[Falling Waveform]
R_fixture= 50.000
V_fixture= 0.0
V_fixture_min= 0.0
V_fixture_max= 0.0
|time   V(typ)   V(min)   V(max)
0s        562mV      521.7mV    563.2mV
391ps     564.3mV    522mV      554.5mV
436ps     564.1mV    523.2mV    493.5mV
498ps     542.6mV    524.8mV    320.3mV
574ps     403.2mV    513mV      163.6mV
666ps     192.1mV    407.4mV    75.22mV
763ps     86.52mV    221.8mV    34.18mV
902ps     29.13mV    73.97mV    11.77mV
1.133ns   5.607mV    13.52mV    2.906mV
50ns      1.468uV    7.92uV     668nV
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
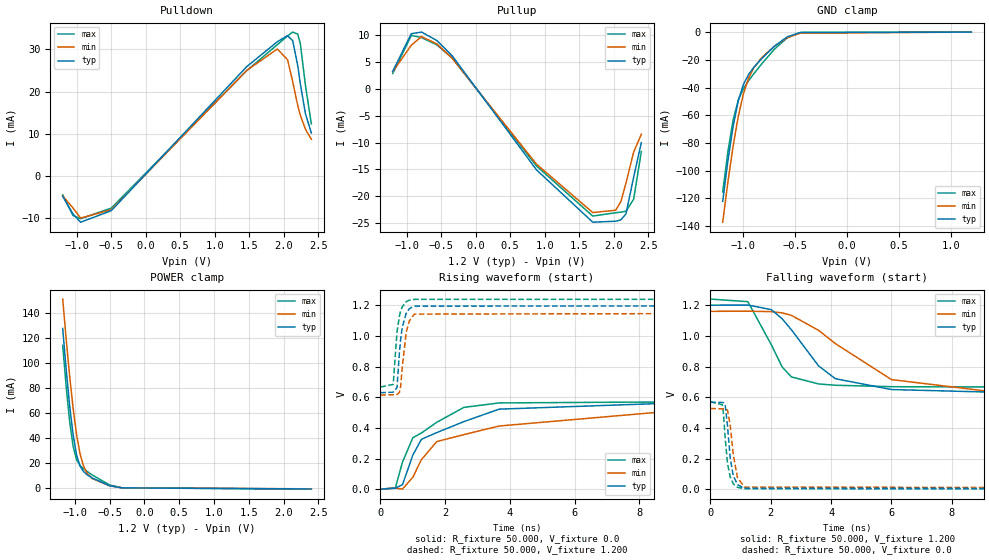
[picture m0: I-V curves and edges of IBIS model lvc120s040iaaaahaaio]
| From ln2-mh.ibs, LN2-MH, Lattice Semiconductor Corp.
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|   Model lvc120s040iaaaahaaio
[Model] lvc120s040iaaaahaaio
| Clamp models do not include dynamic input termination. Please refer to
| the lvc120axxxiaaaahaain model for input termination.
Model_type I/O
Polarity   Non-Inverting
Enable   Active-Low
Vinl =  0.420V
Vinh =  0.780V
Vmeas =  0.600V
Cref =  0.0F
Rref =  1.000M
Vref =  0.0V
C_comp   2.000pF   1.500pF   2.500pF
[Temperature Range]   25.000   0.125k   -40.000
[Voltage Range]   1.200V   1.160V   1.240V
[C Comp Corner]
C_comp   2.000pF   1.500pF   2.500pF
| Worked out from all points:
|   slope of the pulldown table from 0 to 0.18 V, typ, clamps not added: 55.8 ohm
|   slope of the pullup table from 0 to 0.18 V, typ, clamps not added: 55.5 ohm
|   GND clamp passes 1 mA (typ) near -0.50 V on its own axis
|   POWER clamp passes 1 mA (typ) near -0.44 V on its own axis
|   rising waveform, R_fixture 50.000, V_fixture 0.0: 20-80 % time 1.88ns typ, 2.77ns min, 1.25ns max; typ from 0 V to 0.567 V
|   rising waveform, R_fixture 50.000, V_fixture 1.200: 20-80 % time 160ps typ, 177ps min, 152ps max; typ from 0.629 V to 1.2 V
|   falling waveform, R_fixture 50.000, V_fixture 1.200: 20-80 % time 1.44ns typ, 2.4ns min, 837ps max; typ from 1.2 V to 0.629 V
|   falling waveform, R_fixture 50.000, V_fixture 0.0: 20-80 % time 176ps typ, 199ps min, 165ps max; typ from 0.567 V to 0 V
[Pulldown]
|Voltage   I(typ)   I(min)   I(max)
-1.2V     -4.842mA   -4.754mA   -4.504mA
-1.052V   -9.003mA   -7.591mA   -9.375mA
-941mV    -10.98mA   -10mA      -10.17mA
-497mV    -8.254mA   -8.025mA   -7.638mA
1.464V    25.92mA    25.02mA    24.97mA
1.908V    31.84mA    30.11mA    31.14mA
2.056V    33.29mA    27.57mA    33.22mA
2.13V     32.09mA    22.38mA    34.13mA
2.204V    26.12mA    16.67mA    33.64mA
2.241V    21.82mA    14.39mA    31.38mA
2.315V    14.76mA    11.08mA    21.47mA
2.4V      10.19mA    8.701mA    12.37mA
[Pullup]
|Voltage   I(typ)   I(min)   I(max)
-1.2V     3.186mA    3.118mA    2.772mA
-930mV    10.16mA    8.032mA    9.842mA
-782mV    10.45mA    9.62mA     9.433mA
-560mV    8.884mA    8.257mA    8.068mA
-338mV    6.052mA    5.594mA    5.652mA
883mV     -15.08mA   -14.02mA   -14.36mA
1.697V    -24.76mA   -22.98mA   -23.63mA
2.03V     -24.58mA   -22.54mA   -23mA
2.104V    -24.33mA   -20.95mA   -22.9mA
2.178V    -23.21mA   -17.52mA   -22.73mA
2.289V    -16.43mA   -11.78mA   -20.5mA
2.4V      -10.02mA   -8.478mA   -11.68mA
[GND_clamp]
|Voltage   I(typ)   I(min)   I(max)
-1.2V     -122.1mA   -137.1mA   -115.3mA
-1.15V    -92.88mA   -108.2mA   -86.34mA
-1.1V     -68.13mA   -82.44mA   -63.55mA
-1.05V    -49.58mA   -60.89mA   -48.98mA
-1V       -37.73mA   -44.48mA   -40.75mA
-950mV    -30.55mA   -33.19mA   -35.07mA
-900mV    -25.48mA   -25.79mA   -30.1mA
-825mV    -19.21mA   -18.55mA   -23.07mA
-700mV    -10.12mA   -10.12mA   -12.27mA
-575mV    -3.338mA   -4.053mA   -3.949mA
-450mV    -310.5uA   -787.2uA   -256.6uA
1.2V      0A         0A         0A
[POWER_clamp]
|Voltage   I(typ)   I(min)   I(max)
-1.175V   127.9mA    151.5mA    114.4mA
-1.125V   95.11mA    119.3mA    81.3mA
-1.075V   66.05mA    89.76mA    53.26mA
-1.025V   42.55mA    63.81mA    33.28mA
-975mV    26.45mA    42.66mA    22.68mA
-925mV    17.56mA    27.27mA    18.01mA
-875mV    13.18mA    17.5mA     15.4mA
-825mV    10.7mA     11.9mA     13.32mA
-750mV    8.076mA    7.611mA    10.45mA
-500mV    1.821mA    1.817mA    2.516mA
-325mV    164.5uA    258.7uA    189uA
2.4V      -731uA     -642.7uA   -887.3uA
[Ramp]
| variable   typ   min   max
dV/dt_r   0.340/1.881n   0.316/2.772n   0.342/1.252n
dV/dt_f   0.343/1.444n   0.328/2.401n   0.344/0.838n
R_load = 50.000
[Rising Waveform]
R_fixture= 50.000
V_fixture= 0.0
V_fixture_min= 0.0
V_fixture_max= 0.0
|time   V(typ)   V(min)   V(max)
0s        1.465uV    7.911uV    665.2nV
467ps     6.31mV     6.637mV    8.899mV
687ps     29.35mV    995.8uV    177.2mV
1.006ns   222.4mV    78.02mV    335.6mV
1.271ns   325.4mV    192.5mV    366.3mV
1.744ns   368.8mV    310.3mV    436.1mV
2.582ns   440.6mV    355.8mV    533.4mV
3.672ns   522mV      411.9mV    562.6mV
9.734ns   566.9mV    522.7mV    570mV
50ns      567.2mV    526.4mV    570mV
[Rising Waveform]
R_fixture= 50.000
V_fixture= 1.200
V_fixture_min= 1.160
V_fixture_max= 1.240
|time   V(typ)   V(min)   V(max)
0s        629.1mV    613.5mV    666.1mV
399ps     632.6mV    616.1mV    683.2mV
517ps     662.4mV    617.3mV    1.025V
591ps     888.7mV    630.6mV    1.13V
629ps     976.8mV    669.5mV    1.162V
678ps     1.054V     792.3mV    1.189V
802ps     1.149V     1.025V     1.223V
901ps     1.178V     1.099V     1.233V
1.056ns   1.194V     1.142V     1.238V
50ns      1.2V       1.16V      1.24V
[Falling Waveform]
R_fixture= 50.000
V_fixture= 1.200
V_fixture_min= 1.160
V_fixture_max= 1.240
|time   V(typ)   V(min)   V(max)
0s        1.2V       1.16V      1.24V
1.245ns   1.201V     1.161V     1.223V
2.025ns   1.171V     1.158V     940.6mV
2.382ns   1.111V     1.15V      796.7mV
2.685ns   1.04V      1.134V     732.3mV
3.585ns   804.3mV    1.036V     686.4mV
4.145ns   720.4mV    949.1mV    677.8mV
6.001ns   649.8mV    714.7mV    668.4mV
9.492ns   631.8mV    631.7mV    666.3mV
50ns      629mV      613.5mV    666.1mV
[Falling Waveform]
R_fixture= 50.000
V_fixture= 0.0
V_fixture_min= 0.0
V_fixture_max= 0.0
|time   V(typ)   V(min)   V(max)
0s        567.1mV    526.3mV    570mV
397ps     565.7mV    524mV      551.2mV
438ps     564.7mV    524.5mV    489.6mV
495ps     545.5mV    525.6mV    329.4mV
569ps     416.2mV    515.6mV    171mV
662ps     199mV      414.5mV    77.81mV
762ps     87.28mV    223.6mV    34.47mV
902ps     29.16mV    74.02mV    11.78mV
1.132ns   5.648mV    13.63mV    2.921mV
50ns      1.468uV    7.92uV     668nV
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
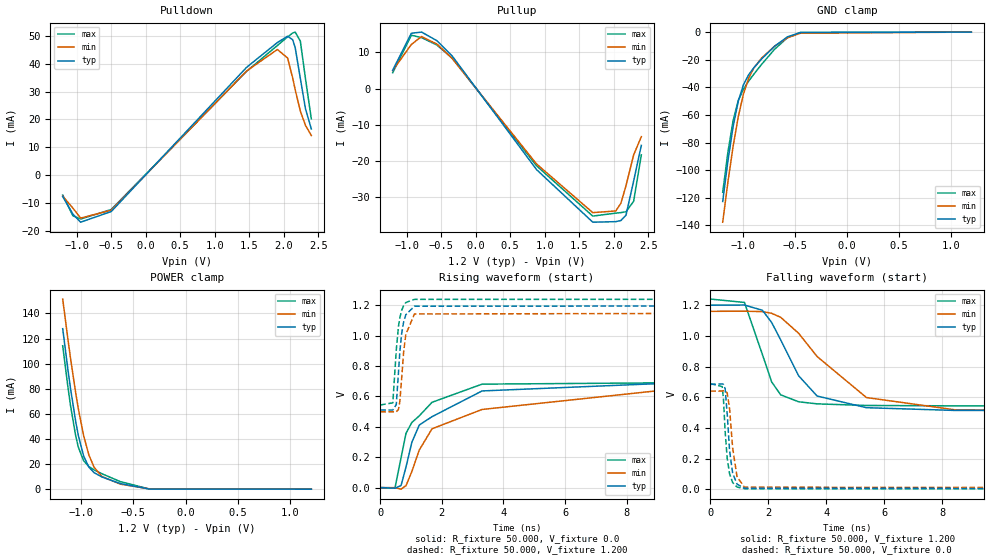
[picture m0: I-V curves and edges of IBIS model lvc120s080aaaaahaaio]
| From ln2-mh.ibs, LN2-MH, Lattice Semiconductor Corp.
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|   Model lvc120s080aaaaahaaio
[Model] lvc120s080aaaaahaaio
| Clamp models do not include dynamic input termination. Please refer to
| the lvc120axxxaaaaahaain model for input termination.
Model_type I/O
Polarity   Non-Inverting
Enable   Active-Low
Vinl =  0.420V
Vinh =  0.780V
Vmeas =  0.600V
Cref =  0.0F
Rref =  1.000M
Vref =  0.0V
C_comp   2.000pF   1.500pF   2.500pF
[Temperature Range]   25.000   0.125k   -40.000
[Voltage Range]   1.200V   1.160V   1.240V
[C Comp Corner]
C_comp   2.000pF   1.500pF   2.500pF
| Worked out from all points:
|   slope of the pulldown table from 0 to 0.18 V, typ, clamps not added: 36.9 ohm
|   slope of the pullup table from 0 to 0.18 V, typ, clamps not added: 37.3 ohm
|   GND clamp passes 1 mA (typ) near -0.50 V on its own axis
|   POWER clamp passes 1 mA (typ) near -0.45 V on its own axis
|   rising waveform, R_fixture 50.000, V_fixture 0.0: 20-80 % time 1.5ns typ, 2.21ns min, 1.01ns max; typ from 0 V to 0.684 V
|   rising waveform, R_fixture 50.000, V_fixture 1.200: 20-80 % time 174ps typ, 186ps min, 168ps max; typ from 0.51 V to 1.2 V
|   falling waveform, R_fixture 50.000, V_fixture 1.200: 20-80 % time 1.23ns typ, 2.02ns min, 700ps max; typ from 1.2 V to 0.51 V
|   falling waveform, R_fixture 50.000, V_fixture 0.0: 20-80 % time 173ps typ, 193ps min, 162ps max; typ from 0.684 V to 0 V
[Pulldown]
|Voltage   I(typ)   I(min)   I(max)
-1.2V     -7.643mA   -7.514mA   -7.124mA
-1.052V   -13.98mA   -11.81mA   -14.55mA
-941mV    -16.85mA   -15.38mA   -15.73mA
-497mV    -13.02mA   -12.56mA   -12.29mA
1.464V    38.7mA     37.38mA    37.29mA
1.908V    47.55mA    45.07mA    46.49mA
2.056V    49.83mA    42.04mA    49.58mA
2.13V     48.57mA    34.9mA     50.98mA
2.167V    45.71mA    30.58mA    51.31mA
2.241V    34.72mA    23mA       48.07mA
2.315V    23.86mA    17.9mA     34.66mA
2.4V      16.59mA    14.23mA    20.22mA
[Pullup]
|Voltage   I(typ)   I(min)   I(max)
-1.2V     5.078mA    4.999mA    4.395mA
-930mV    15.33mA    12.22mA    14.77mA
-782mV    15.65mA    14.42mA    14.12mA
-560mV    13.27mA    12.33mA    12.06mA
-338mV    9.009mA    8.334mA    8.419mA
883mV     -22.47mA   -20.9mA    -21.41mA
1.697V    -37.04mA   -34.39mA   -35.35mA
2.03V     -36.89mA   -33.93mA   -34.53mA
2.104V    -36.58mA   -31.79mA   -34.38mA
2.178V    -35.11mA   -26.95mA   -34.15mA
2.289V    -25.61mA   -18.39mA   -31.24mA
2.4V      -15.75mA   -13.34mA   -18.38mA
[GND_clamp]
|Voltage   I(typ)   I(min)   I(max)
-1.2V     -122.7mA   -137.7mA   -116.1mA
-1.15V    -93.51mA   -108.7mA   -87.11mA
-1.1V     -68.71mA   -82.95mA   -64.25mA
-1.05V    -50.11mA   -61.37mA   -49.6mA
-1V       -38.2mA    -44.91mA   -41.31mA
-950mV    -30.97mA   -33.58mA   -35.58mA
-900mV    -25.86mA   -26.14mA   -30.55mA
-825mV    -19.51mA   -18.84mA   -23.44mA
-700mV    -10.31mA   -10.31mA   -12.51mA
-575mV    -3.428mA   -4.153mA   -4.057mA
-450mV    -324.6uA   -816.9uA   -269.6uA
1.2V      0A         0A         0A
[POWER_clamp]
|Voltage   I(typ)   I(min)   I(max)
-1.175V   127.9mA    151.5mA    114.3mA
-1.125V   95.1mA     119.3mA    81.28mA
-1.1V     80mA       104.1mA    66.45mA
-1.05V    53.45mA    76.24mA    42.06mA
-1.025V   42.52mA    63.79mA    33.25mA
-975mV    26.41mA    42.63mA    22.64mA
-925mV    17.53mA    27.24mA    17.96mA
-875mV    13.14mA    17.46mA    15.36mA
-800mV    9.702mA    10.06mA    12.29mA
-625mV    4.476mA    4.013mA    6.017mA
-350mV    147.7uA    296.5uA    176.7uA
1.2V      0A         0A         0A
[Ramp]
| variable   typ   min   max
dV/dt_r   0.410/1.501n   0.384/2.212n   0.413/1.006n
dV/dt_f   0.414/1.228n   0.397/2.018n   0.418/0.700n
R_load = 50.000
[Rising Waveform]
R_fixture= 50.000
V_fixture= 0.0
V_fixture_min= 0.0
V_fixture_max= 0.0
|time   V(typ)   V(min)   V(max)
0s        1.143uV    6.223uV    521.7nV
477ps     -3.854mV   -391.3uV   -2.857mV
675ps     13.62mV    -10.38mV   196mV
836ps     135.7mV    12.79mV    357.3mV
1.026ns   298.4mV    106mV      428.7mV
1.266ns   411.4mV    247mV      471.7mV
1.681ns   466.5mV    386.8mV    561.1mV
3.305ns   635.7mV    513.9mV    680.4mV
8.951ns   683.3mV    635.8mV    688.7mV
50ns      683.6mV    639.6mV    688.7mV
[Rising Waveform]
R_fixture= 50.000
V_fixture= 1.200
V_fixture_min= 1.160
V_fixture_max= 1.240
|time   V(typ)   V(min)   V(max)
0s        510.2mV    498.2mV    543.2mV
407ps     509.7mV    498.3mV    557.7mV
519ps     545.8mV    498.1mV    902.8mV
590ps     753.8mV    513.3mV    1.059V
635ps     892.3mV    565.7mV    1.117V
695ps     1.014V     721.4mV    1.166V
759ps     1.09V      892.7mV    1.197V
829ps     1.137V     1.007V     1.217V
1.11ns    1.193V     1.142V     1.238V
50ns      1.2V       1.16V      1.24V
[Falling Waveform]
R_fixture= 50.000
V_fixture= 1.200
V_fixture_min= 1.160
V_fixture_max= 1.240
|time   V(typ)   V(min)   V(max)
0s        1.2V       1.16V      1.24V
1.179ns   1.201V     1.161V     1.218V
1.798ns   1.167V     1.158V     878.1mV
2.118ns   1.087V     1.147V     699.3mV
2.428ns   973.7mV    1.121V     615.3mV
3.046ns   739.8mV    1.017V     570mV
3.686ns   607.4mV    864.9mV    556.4mV
5.386ns   531.4mV    597.6mV    545.9mV
8.462ns   513.4mV    517mV      543.4mV
50ns      510.2mV    498.2mV    543.2mV
[Falling Waveform]
R_fixture= 50.000
V_fixture= 0.0
V_fixture_min= 0.0
V_fixture_max= 0.0
|time   V(typ)   V(min)   V(max)
0s        683.6mV    639.6mV    688.7mV
411ps     686.6mV    640.3mV    669.1mV
454ps     684.2mV    642mV      590.5mV
513ps     655.3mV    642.5mV    375.6mV
584ps     490.5mV    627.8mV    200.5mV
666ps     250.1mV    524.1mV    100.3mV
772ps     104.4mV    267.7mV    42.74mV
923ps     32.55mV    81.22mV    13.73mV
1.179ns   5.703mV    12.96mV    3.204mV
50ns      1.145uV    6.228uV    523.8nV
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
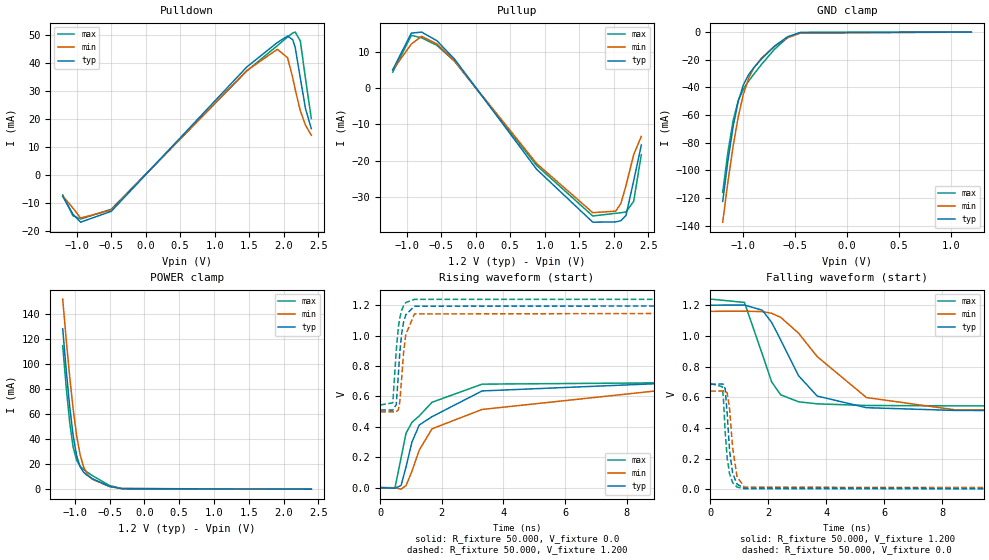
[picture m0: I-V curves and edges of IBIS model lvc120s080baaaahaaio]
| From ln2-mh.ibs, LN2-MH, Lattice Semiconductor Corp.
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|   Model lvc120s080baaaahaaio
[Model] lvc120s080baaaahaaio
| Clamp models do not include dynamic input termination. Please refer to
| the lvc120axxxbaaaahaain model for input termination.
Model_type I/O
Polarity   Non-Inverting
Enable   Active-Low
Vinl =  0.420V
Vinh =  0.780V
Vmeas =  0.600V
Cref =  0.0F
Rref =  1.000M
Vref =  0.0V
C_comp   2.000pF   1.500pF   2.500pF
[Temperature Range]   25.000   0.125k   -40.000
[Voltage Range]   1.200V   1.160V   1.240V
[C Comp Corner]
C_comp   2.000pF   1.500pF   2.500pF
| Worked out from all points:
|   slope of the pulldown table from 0 to 0.18 V, typ, clamps not added: 36.9 ohm
|   slope of the pullup table from 0 to 0.18 V, typ, clamps not added: 38 ohm
|   GND clamp passes 1 mA (typ) near -0.50 V on its own axis
|   POWER clamp passes 1 mA (typ) near -0.43 V on its own axis
|   rising waveform, R_fixture 50.000, V_fixture 0.0: 20-80 % time 1.5ns typ, 2.21ns min, 1.01ns max; typ from 0 V to 0.684 V
|   rising waveform, R_fixture 50.000, V_fixture 1.200: 20-80 % time 174ps typ, 186ps min, 168ps max; typ from 0.51 V to 1.2 V
|   falling waveform, R_fixture 50.000, V_fixture 1.200: 20-80 % time 1.23ns typ, 2.02ns min, 700ps max; typ from 1.2 V to 0.51 V
|   falling waveform, R_fixture 50.000, V_fixture 0.0: 20-80 % time 173ps typ, 193ps min, 162ps max; typ from 0.684 V to 0 V
[Pulldown]
|Voltage   I(typ)   I(min)   I(max)
-1.2V     -7.635mA   -7.504mA   -7.116mA
-1.052V   -13.96mA   -11.8mA    -14.53mA
-941mV    -16.83mA   -15.35mA   -15.7mA
-497mV    -12.94mA   -12.48mA   -12.21mA
1.464V    38.5mA     37.2mA     37.09mA
1.908V    47.25mA    44.85mA    46.14mA
2.056V    49.55mA    41.85mA    49.24mA
2.13V     48.31mA    34.76mA    50.65mA
2.167V    45.48mA    30.45mA    50.98mA
2.241V    34.55mA    22.91mA    47.8mA
2.315V    23.74mA    17.82mA    34.49mA
2.4V      16.51mA    14.16mA    20.11mA
[Pullup]
|Voltage   I(typ)   I(min)   I(max)
-1.2V     4.993mA    4.928mA    4.304mA
-930mV    15.07mA    12.05mA    14.45mA
-782mV    15.35mA    14.2mA     13.78mA
-560mV    12.97mA    12.11mA    11.71mA
-301mV    7.84mA     7.308mA    7.274mA
883mV     -22.37mA   -20.8mA    -21.31mA
1.697V    -36.95mA   -34.33mA   -35.25mA
2.03V     -36.87mA   -33.91mA   -34.5mA
2.104V    -36.55mA   -31.77mA   -34.36mA
2.178V    -35.08mA   -26.93mA   -34.13mA
2.289V    -25.6mA    -18.38mA   -31.23mA
2.4V      -15.74mA   -13.33mA   -18.37mA
[GND_clamp]
|Voltage   I(typ)   I(min)   I(max)
-1.2V     -122.6mA   -137.6mA   -116mA
-1.15V    -93.41mA   -108.6mA   -87.01mA
-1.1V     -68.62mA   -82.86mA   -64.16mA
-1.05V    -50.02mA   -61.28mA   -49.51mA
-1V       -38.12mA   -44.82mA   -41.23mA
-950mV    -30.88mA   -33.5mA    -35.49mA
-900mV    -25.78mA   -26.06mA   -30.47mA
-825mV    -19.44mA   -18.76mA   -23.36mA
-700mV    -10.25mA   -10.24mA   -12.44mA
-575mV    -3.381mA   -4.102mA   -4.007mA
-450mV    -315.1uA   -796.4uA   -262uA
1.2V      0A         0A         0A
[POWER_clamp]
|Voltage   I(typ)   I(min)   I(max)
-1.175V   127.9mA    151.6mA    114.4mA
-1.125V   95.2mA     119.4mA    81.41mA
-1.075V   66.17mA    89.85mA    53.4mA
-1.025V   42.7mA     63.91mA    33.48mA
-975mV    26.64mA    42.78mA    22.93mA
-925mV    17.79mA    27.41mA    18.29mA
-875mV    13.42mA    17.66mA    15.69mA
-825mV    10.95mA    12.07mA    13.61mA
-750mV    8.323mA    7.791mA    10.74mA
-500mV    2.04mA     1.98mA     2.782mA
-325mV    310.3uA    373.2uA    366.8uA
2.4V      -105uA     -106.2uA   -106.1uA
[Ramp]
| variable   typ   min   max
dV/dt_r   0.410/1.501n   0.384/2.212n   0.413/1.006n
dV/dt_f   0.414/1.229n   0.397/2.018n   0.418/0.700n
R_load = 50.000
[Rising Waveform]
R_fixture= 50.000
V_fixture= 0.0
V_fixture_min= 0.0
V_fixture_max= 0.0
|time   V(typ)   V(min)   V(max)
0s        1.143uV    6.223uV    521.7nV
477ps     -3.854mV   -391.3uV   -2.857mV
675ps     13.62mV    -10.38mV   196mV
836ps     135.7mV    12.79mV    357.3mV
1.026ns   298.4mV    106mV      428.7mV
1.266ns   411.4mV    247mV      471.7mV
1.681ns   466.5mV    386.8mV    561.1mV
3.305ns   635.7mV    513.9mV    680.4mV
8.951ns   683.3mV    635.8mV    688.7mV
50ns      683.6mV    639.6mV    688.7mV
[Rising Waveform]
R_fixture= 50.000
V_fixture= 1.200
V_fixture_min= 1.160
V_fixture_max= 1.240
|time   V(typ)   V(min)   V(max)
0s        510.2mV    498.2mV    543.2mV
407ps     509.7mV    498.3mV    557.7mV
519ps     545.8mV    498.1mV    902.8mV
590ps     753.8mV    513.3mV    1.059V
635ps     892.3mV    565.7mV    1.117V
695ps     1.014V     721.4mV    1.166V
759ps     1.09V      892.7mV    1.197V
829ps     1.137V     1.007V     1.217V
1.11ns    1.193V     1.142V     1.238V
50ns      1.2V       1.16V      1.24V
[Falling Waveform]
R_fixture= 50.000
V_fixture= 1.200
V_fixture_min= 1.160
V_fixture_max= 1.240
|time   V(typ)   V(min)   V(max)
0s        1.2V       1.16V      1.24V
1.179ns   1.201V     1.161V     1.218V
1.798ns   1.167V     1.158V     878.1mV
2.118ns   1.087V     1.147V     699.3mV
2.428ns   973.7mV    1.121V     615.3mV
3.046ns   739.8mV    1.017V     570mV
3.686ns   607.4mV    864.9mV    556.4mV
5.386ns   531.4mV    597.6mV    545.9mV
8.462ns   513.4mV    517mV      543.4mV
50ns      510.2mV    498.2mV    543.2mV
[Falling Waveform]
R_fixture= 50.000
V_fixture= 0.0
V_fixture_min= 0.0
V_fixture_max= 0.0
|time   V(typ)   V(min)   V(max)
0s        683.6mV    639.6mV    688.7mV
411ps     686.6mV    640.3mV    669.1mV
454ps     684.2mV    642mV      590.5mV
513ps     655.3mV    642.5mV    375.6mV
584ps     490.5mV    627.8mV    200.5mV
666ps     250.1mV    524.1mV    100.3mV
772ps     104.4mV    267.7mV    42.74mV
923ps     32.55mV    81.22mV    13.73mV
1.179ns   5.703mV    12.96mV    3.204mV
50ns      1.145uV    6.228uV    523.8nV
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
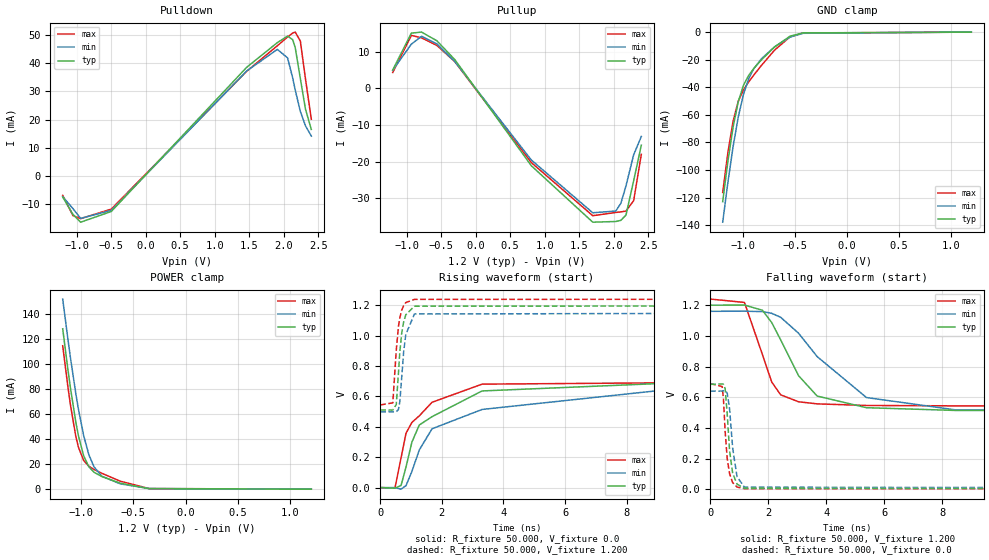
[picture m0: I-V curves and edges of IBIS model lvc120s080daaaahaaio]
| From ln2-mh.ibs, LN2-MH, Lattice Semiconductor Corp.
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|   Model lvc120s080daaaahaaio
[Model] lvc120s080daaaahaaio
| Clamp models do not include dynamic input termination. Please refer to
| the lvc120axxxdaaaahaain model for input termination.
Model_type I/O
Polarity   Non-Inverting
Enable   Active-Low
Vinl =  0.420V
Vinh =  0.780V
Vmeas =  0.600V
Cref =  0.0F
Rref =  1.000M
Vref =  0.0V
C_comp   2.000pF   1.500pF   2.500pF
[Temperature Range]   25.000   0.125k   -40.000
[Voltage Range]   1.200V   1.160V   1.240V
[C Comp Corner]
C_comp   2.000pF   1.500pF   2.500pF
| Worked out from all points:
|   slope of the pulldown table from 0 to 0.18 V, typ, clamps not added: 38.3 ohm
|   slope of the pullup table from 0 to 0.18 V, typ, clamps not added: 38 ohm
|   GND clamp passes 1 mA (typ) near -0.47 V on its own axis
|   POWER clamp passes 1 mA (typ) near -0.43 V on its own axis
|   rising waveform, R_fixture 50.000, V_fixture 0.0: 20-80 % time 1.5ns typ, 2.21ns min, 1.01ns max; typ from 0 V to 0.684 V
|   rising waveform, R_fixture 50.000, V_fixture 1.200: 20-80 % time 174ps typ, 186ps min, 168ps max; typ from 0.51 V to 1.2 V
|   falling waveform, R_fixture 50.000, V_fixture 1.200: 20-80 % time 1.23ns typ, 2.02ns min, 700ps max; typ from 1.2 V to 0.51 V
|   falling waveform, R_fixture 50.000, V_fixture 0.0: 20-80 % time 173ps typ, 193ps min, 162ps max; typ from 0.684 V to 0 V
[Pulldown]
|Voltage   I(typ)   I(min)   I(max)
-1.2V     -7.419mA   -7.326mA   -6.854mA
-1.052V   -13.57mA   -11.52mA   -13.99mA
-941mV    -16.34mA   -14.99mA   -15.09mA
-497mV    -12.55mA   -12.17mA   -11.71mA
1.464V    38.5mA     37.2mA     37.09mA
1.908V    47.25mA    44.85mA    46.14mA
2.056V    49.55mA    41.85mA    49.24mA
2.13V     48.31mA    34.76mA    50.65mA
2.167V    45.48mA    30.45mA    50.98mA
2.241V    34.55mA    22.91mA    47.8mA
2.315V    23.74mA    17.82mA    34.49mA
2.4V      16.51mA    14.16mA    20.11mA
[Pullup]
|Voltage   I(typ)   I(min)   I(max)
-1.2V     4.993mA    4.928mA    4.304mA
-930mV    15.07mA    12.05mA    14.45mA
-782mV    15.35mA    14.2mA     13.78mA
-560mV    12.97mA    12.11mA    11.71mA
-301mV    7.84mA     7.308mA    7.274mA
809mV     -21.18mA   -19.62mA   -20.31mA
1.697V    -36.56mA   -33.99mA   -34.79mA
2.03V     -36.37mA   -33.51mA   -33.9mA
2.104V    -36.05mA   -31.4mA    -33.75mA
2.178V    -34.61mA   -26.63mA   -33.52mA
2.289V    -25.26mA   -18.16mA   -30.68mA
2.4V      -15.52mA   -13.16mA   -18.06mA
[GND_clamp]
|Voltage   I(typ)   I(min)   I(max)
-1.2V     -123mA     -137.9mA   -116.3mA
-1.15V    -93.77mA   -109mA     -87.45mA
-1.1V     -69.04mA   -83.2mA    -64.7mA
-1.05V    -50.52mA   -61.66mA   -50.16mA
-1V       -38.68mA   -45.25mA   -41.93mA
-950mV    -31.48mA   -33.96mA   -36.21mA
-900mV    -26.38mA   -26.55mA   -31.19mA
-825mV    -20.04mA   -19.26mA   -24.07mA
-700mV    -10.83mA   -10.73mA   -13.14mA
-550mV    -2.967mA   -3.644mA   -3.468mA
-425mV    -588.2uA   -868.5uA   -635.3uA
1.2V      -845nA     5.241uA    -30.51uA
[POWER_clamp]
|Voltage   I(typ)   I(min)   I(max)
-1.175V   127.9mA    151.6mA    114.4mA
-1.125V   95.2mA     119.4mA    81.41mA
-1.1V     80.12mA    104.2mA    66.6mA
-1.05V    53.6mA     76.35mA    42.26mA
-1.025V   42.7mA     63.91mA    33.48mA
-975mV    26.64mA    42.78mA    22.93mA
-925mV    17.79mA    27.41mA    18.29mA
-875mV    13.42mA    17.66mA    15.69mA
-800mV    9.995mA    10.28mA    12.63mA
-625mV    4.774mA    4.24mA     6.369mA
-350mV    398.5uA    489.6uA    483.6uA
1.2V      0A         0A         49.13uA
[Ramp]
| variable   typ   min   max
dV/dt_r   0.410/1.501n   0.384/2.212n   0.413/1.006n
dV/dt_f   0.414/1.228n   0.397/2.018n   0.418/0.700n
R_load = 50.000
[Rising Waveform]
R_fixture= 50.000
V_fixture= 0.0
V_fixture_min= 0.0
V_fixture_max= 0.0
|time   V(typ)   V(min)   V(max)
0s        1.143uV    6.223uV    521.7nV
477ps     -3.854mV   -391.3uV   -2.857mV
675ps     13.62mV    -10.38mV   196mV
836ps     135.7mV    12.79mV    357.3mV
1.026ns   298.4mV    106mV      428.7mV
1.266ns   411.4mV    247mV      471.7mV
1.681ns   466.5mV    386.8mV    561.1mV
3.305ns   635.7mV    513.9mV    680.4mV
8.935ns   683.3mV    635.7mV    688.7mV
50ns      683.6mV    639.6mV    688.7mV
[Rising Waveform]
R_fixture= 50.000
V_fixture= 1.200
V_fixture_min= 1.160
V_fixture_max= 1.240
|time   V(typ)   V(min)   V(max)
0s        510.2mV    498.2mV    543.2mV
407ps     509.7mV    498.3mV    557.7mV
519ps     545.8mV    498.1mV    902.8mV
590ps     753.8mV    513.3mV    1.059V
635ps     892.3mV    565.7mV    1.117V
695ps     1.014V     721.4mV    1.166V
759ps     1.09V      892.7mV    1.197V
829ps     1.137V     1.007V     1.217V
1.11ns    1.193V     1.142V     1.238V
50ns      1.2V       1.16V      1.24V
[Falling Waveform]
R_fixture= 50.000
V_fixture= 1.200
V_fixture_min= 1.160
V_fixture_max= 1.240
|time   V(typ)   V(min)   V(max)
0s        1.2V       1.16V      1.24V
1.179ns   1.201V     1.161V     1.218V
1.798ns   1.167V     1.158V     878.1mV
2.118ns   1.087V     1.147V     699.3mV
2.428ns   973.7mV    1.121V     615.3mV
3.046ns   739.8mV    1.017V     570mV
3.686ns   607.4mV    864.9mV    556.4mV
5.386ns   531.4mV    597.6mV    545.9mV
8.472ns   513.4mV    516.9mV    543.4mV
50ns      510.2mV    498.2mV    543.2mV
[Falling Waveform]
R_fixture= 50.000
V_fixture= 0.0
V_fixture_min= 0.0
V_fixture_max= 0.0
|time   V(typ)   V(min)   V(max)
0s        683.6mV    639.6mV    688.7mV
411ps     686.6mV    640.3mV    669.1mV
454ps     684.2mV    642mV      590.5mV
513ps     655.3mV    642.5mV    375.6mV
584ps     490.5mV    627.8mV    200.5mV
666ps     250.1mV    524.1mV    100.3mV
772ps     104.4mV    267.7mV    42.74mV
923ps     32.55mV    81.22mV    13.73mV
1.179ns   5.703mV    12.96mV    3.204mV
50ns      1.145uV    6.228uV    523.7nV
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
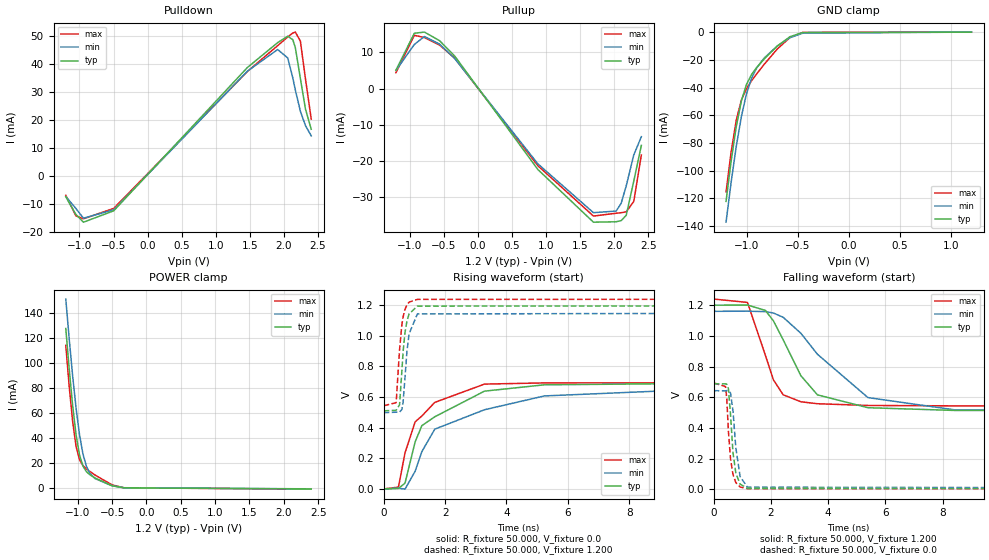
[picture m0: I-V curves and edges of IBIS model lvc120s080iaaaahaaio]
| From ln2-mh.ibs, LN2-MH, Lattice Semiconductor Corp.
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|   Model lvc120s080iaaaahaaio
[Model] lvc120s080iaaaahaaio
| Clamp models do not include dynamic input termination. Please refer to
| the lvc120axxxiaaaahaain model for input termination.
Model_type I/O
Polarity   Non-Inverting
Enable   Active-Low
Vinl =  0.420V
Vinh =  0.780V
Vmeas =  0.600V
Cref =  0.0F
Rref =  1.000M
Vref =  0.0V
C_comp   2.000pF   1.500pF   2.500pF
[Temperature Range]   25.000   0.125k   -40.000
[Voltage Range]   1.200V   1.160V   1.240V
[C Comp Corner]
C_comp   2.000pF   1.500pF   2.500pF
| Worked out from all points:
|   slope of the pulldown table from 0 to 0.18 V, typ, clamps not added: 37.3 ohm
|   slope of the pullup table from 0 to 0.18 V, typ, clamps not added: 37.3 ohm
|   GND clamp passes 1 mA (typ) near -0.50 V on its own axis
|   POWER clamp passes 1 mA (typ) near -0.44 V on its own axis
|   rising waveform, R_fixture 50.000, V_fixture 0.0: 20-80 % time 1.49ns typ, 2.19ns min, 997ps max; typ from 0 V to 0.687 V
|   rising waveform, R_fixture 50.000, V_fixture 1.200: 20-80 % time 169ps typ, 182ps min, 163ps max; typ from 0.51 V to 1.2 V
|   falling waveform, R_fixture 50.000, V_fixture 1.200: 20-80 % time 1.23ns typ, 2.02ns min, 700ps max; typ from 1.2 V to 0.51 V
|   falling waveform, R_fixture 50.000, V_fixture 0.0: 20-80 % time 173ps typ, 193ps min, 162ps max; typ from 0.687 V to 0 V
[Pulldown]
|Voltage   I(typ)   I(min)   I(max)
-1.2V     -7.568mA   -7.445mA   -7.032mA
-1.052V   -13.82mA   -11.7mA    -14.33mA
-941mV    -16.61mA   -15.19mA   -15.41mA
-497mV    -12.54mA   -12.17mA   -11.69mA
1.464V    38.62mA    37.31mA    37.21mA
1.908V    47.5mA     45.03mA    46.43mA
2.056V    49.79mA    42mA       49.53mA
2.13V     48.53mA    34.88mA    50.94mA
2.167V    45.68mA    30.56mA    51.26mA
2.241V    34.69mA    22.99mA    48.03mA
2.315V    23.84mA    17.89mA    34.64mA
2.4V      16.58mA    14.22mA    20.21mA
[Pullup]
|Voltage   I(typ)   I(min)   I(max)
-1.2V     5.079mA    5mA        4.396mA
-930mV    15.33mA    12.23mA    14.77mA
-782mV    15.65mA    14.42mA    14.12mA
-560mV    13.27mA    12.33mA    12.06mA
-338mV    9.007mA    8.333mA    8.416mA
883mV     -22.46mA   -20.89mA   -21.4mA
1.697V    -37.04mA   -34.4mA    -35.34mA
2.03V     -36.92mA   -33.95mA   -34.56mA
2.104V    -36.6mA    -31.81mA   -34.41mA
2.178V    -35.13mA   -26.97mA   -34.18mA
2.289V    -25.64mA   -18.4mA    -31.28mA
2.4V      -15.76mA   -13.34mA   -18.41mA
[GND_clamp]
|Voltage   I(typ)   I(min)   I(max)
-1.2V     -122.1mA   -137.1mA   -115.3mA
-1.15V    -92.88mA   -108.2mA   -86.34mA
-1.1V     -68.13mA   -82.44mA   -63.55mA
-1.05V    -49.58mA   -60.89mA   -48.98mA
-1V       -37.73mA   -44.48mA   -40.75mA
-950mV    -30.55mA   -33.19mA   -35.07mA
-900mV    -25.48mA   -25.79mA   -30.1mA
-825mV    -19.21mA   -18.55mA   -23.07mA
-700mV    -10.12mA   -10.12mA   -12.27mA
-575mV    -3.338mA   -4.053mA   -3.949mA
-450mV    -310.5uA   -787.2uA   -256.6uA
1.2V      0A         0A         0A
[POWER_clamp]
|Voltage   I(typ)   I(min)   I(max)
-1.175V   127.9mA    151.5mA    114.4mA
-1.125V   95.11mA    119.3mA    81.3mA
-1.075V   66.05mA    89.76mA    53.26mA
-1.025V   42.55mA    63.81mA    33.28mA
-975mV    26.45mA    42.66mA    22.68mA
-925mV    17.56mA    27.27mA    18.01mA
-875mV    13.18mA    17.5mA     15.4mA
-825mV    10.7mA     11.9mA     13.32mA
-750mV    8.076mA    7.611mA    10.45mA
-500mV    1.821mA    1.817mA    2.516mA
-325mV    164.5uA    258.7uA    189uA
2.4V      -731uA     -642.7uA   -887.3uA
[Ramp]
| variable   typ   min   max
dV/dt_r   0.412/1.490n   0.386/2.194n   0.416/0.997n
dV/dt_f   0.414/1.229n   0.397/2.015n   0.418/0.700n
R_load = 50.000
[Rising Waveform]
R_fixture= 50.000
V_fixture= 0.0
V_fixture_min= 0.0
V_fixture_max= 0.0
|time   V(typ)   V(min)   V(max)
0s        1.143uV    6.223uV    521.7nV
482ps     3.274mV    5.369mV    11.92mV
696ps     37.92mV    -1.473mV   235.6mV
1.025ns   307.1mV    115.5mV    438.1mV
1.245ns   413.5mV    244.1mV    476.5mV
1.665ns   471.3mV    390.4mV    565.3mV
3.284ns   638.7mV    517.2mV    684.7mV
5.233ns   680mV      607.4mV    692.4mV
8.926ns   686.6mV    638.8mV    693mV
50ns      686.9mV    642.6mV    693mV
[Rising Waveform]
R_fixture= 50.000
V_fixture= 1.200
V_fixture_min= 1.160
V_fixture_max= 1.240
|time   V(typ)   V(min)   V(max)
0s        510.2mV    498.2mV    543.2mV
407ps     513.7mV    501.1mV    563.5mV
518ps     549.3mV    501.7mV    909.1mV
592ps     767.6mV    518.5mV    1.071V
634ps     897.4mV    568.3mV    1.124V
694ps     1.02V      724.4mV    1.172V
759ps     1.097V     899.4mV    1.202V
829ps     1.143V     1.013V     1.22V
1.099ns   1.194V     1.143V     1.238V
50ns      1.2V       1.16V      1.24V
[Falling Waveform]
R_fixture= 50.000
V_fixture= 1.200
V_fixture_min= 1.160
V_fixture_max= 1.240
|time   V(typ)   V(min)   V(max)
0s        1.2V       1.16V      1.24V
1.178ns   1.201V     1.161V     1.218V
1.805ns   1.166V     1.158V     873.3mV
2.085ns   1.098V     1.149V     713.1mV
2.427ns   974.1mV    1.121V     615.5mV
3.045ns   740.1mV    1.017V     570mV
3.625ns   615.2mV    879.9mV    557.3mV
5.391ns   531.3mV    597.3mV    545.9mV
8.422ns   513.5mV    517.4mV    543.4mV
50ns      510.2mV    498.2mV    543.2mV
[Falling Waveform]
R_fixture= 50.000
V_fixture= 0.0
V_fixture_min= 0.0
V_fixture_max= 0.0
|time   V(typ)   V(min)   V(max)
0s        686.8mV    642.6mV    693mV
411ps     687.1mV    641.3mV    669.4mV
454ps     684.5mV    642.6mV    590.6mV
512ps     656.5mV    642.9mV    379.1mV
585ps     487.2mV    627.3mV    198.8mV
672ps     237.8mV    511.5mV    95.54mV
771ps     105.2mV    269.8mV    43.08mV
923ps     32.56mV    81.26mV    13.69mV
1.18ns    5.625mV    12.87mV    3.229mV
50ns      1.145uV    6.228uV    523.7nV
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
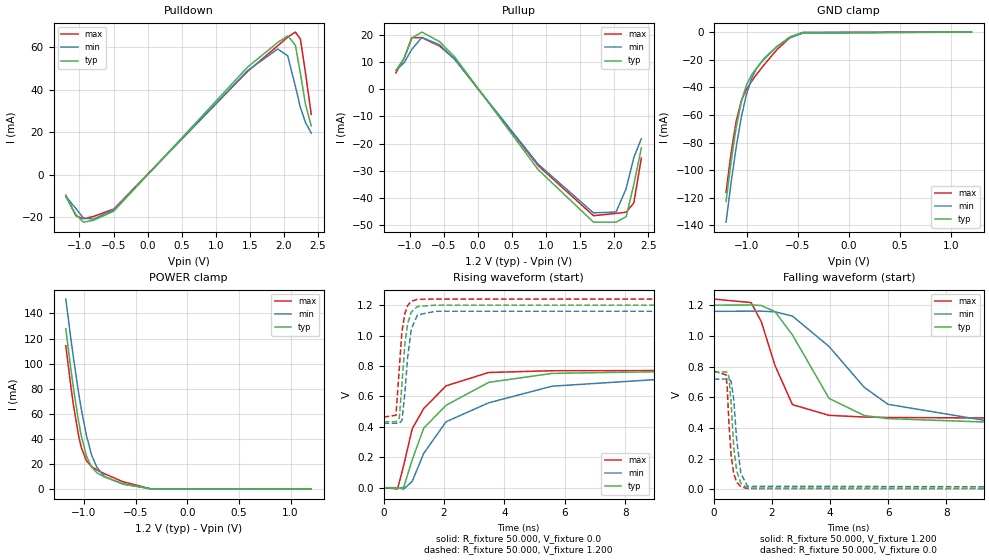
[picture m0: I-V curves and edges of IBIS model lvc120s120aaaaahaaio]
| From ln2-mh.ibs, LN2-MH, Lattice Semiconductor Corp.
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|   Model lvc120s120aaaaahaaio
[Model] lvc120s120aaaaahaaio
| Clamp models do not include dynamic input termination. Please refer to
| the lvc120axxxaaaaahaain model for input termination.
Model_type I/O
Polarity   Non-Inverting
Enable   Active-Low
Vinl =  0.420V
Vinh =  0.780V
Vmeas =  0.600V
Cref =  0.0F
Rref =  1.000M
Vref =  0.0V
C_comp   2.000pF   1.500pF   2.500pF
[Temperature Range]   25.000   0.125k   -40.000
[Voltage Range]   1.200V   1.160V   1.240V
[C Comp Corner]
C_comp   2.000pF   1.500pF   2.500pF
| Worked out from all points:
|   slope of the pulldown table from 0 to 0.18 V, typ, clamps not added: 28.2 ohm
|   slope of the pullup table from 0 to 0.18 V, typ, clamps not added: 28.5 ohm
|   GND clamp passes 1 mA (typ) near -0.50 V on its own axis
|   POWER clamp passes 1 mA (typ) near -0.45 V on its own axis
|   rising waveform, R_fixture 50.000, V_fixture 0.0: 20-80 % time 1.72ns typ, 2.55ns min, 1.11ns max; typ from 0 V to 0.763 V
|   rising waveform, R_fixture 50.000, V_fixture 1.200: 20-80 % time 192ps typ, 204ps min, 178ps max; typ from 0.433 V to 1.2 V
|   falling waveform, R_fixture 50.000, V_fixture 1.200: 20-80 % time 1.41ns typ, 2.26ns min, 811ps max; typ from 1.2 V to 0.433 V
|   falling waveform, R_fixture 50.000, V_fixture 0.0: 20-80 % time 175ps typ, 198ps min, 162ps max; typ from 0.763 V to 0 V
[Pulldown]
|Voltage   I(typ)   I(min)   I(max)
-1.2V     -10.29mA   -10.12mA   -9.55mA
-1.052V   -18.66mA   -15.79mA   -19.23mA
-941mV    -22.22mA   -20.34mA   -20.62mA
-793mV    -21.33mA   -20.77mA   -19.52mA
-497mV    -17.06mA   -16.46mA   -16.05mA
1.464V    50.6mA     48.95mA    48.6mA
1.908V    62.24mA    59.17mA    60.67mA
2.056V    65.34mA    55.96mA    64.72mA
2.167V    61.02mA    41.77mA    67.12mA
2.241V    47.77mA    31.68mA    63.89mA
2.315V    33.27mA    24.7mA     48.16mA
2.4V      23.04mA    19.67mA    28.43mA
[Pullup]
|Voltage   I(typ)   I(min)   I(max)
-1.2V     6.934mA    6.85mA     5.965mA
-1.078V   11.4mA     9.769mA    11.47mA
-967mV    18.78mA    14.6mA     18.89mA
-819mV    20.96mA    19.04mA    18.9mA
-560mV    17.46mA    16.27mA    15.82mA
-338mV    11.82mA    10.97mA    11.01mA
883mV     -29.5mA    -27.5mA    -28.01mA
1.697V    -48.89mA   -45.49mA   -46.52mA
2.03V     -48.91mA   -45.15mA   -45.68mA
2.178V    -46.84mA   -36.51mA   -45.22mA
2.289V    -35.07mA   -25.16mA   -41.84mA
2.4V      -21.64mA   -18.25mA   -25.36mA
[GND_clamp]
|Voltage   I(typ)   I(min)   I(max)
-1.2V     -122.7mA   -137.7mA   -116.1mA
-1.15V    -93.51mA   -108.7mA   -87.11mA
-1.1V     -68.71mA   -82.95mA   -64.25mA
-1.05V    -50.11mA   -61.37mA   -49.6mA
-1V       -38.2mA    -44.91mA   -41.31mA
-950mV    -30.97mA   -33.58mA   -35.58mA
-900mV    -25.86mA   -26.14mA   -30.55mA
-825mV    -19.51mA   -18.84mA   -23.44mA
-700mV    -10.31mA   -10.31mA   -12.51mA
-575mV    -3.428mA   -4.153mA   -4.057mA
-450mV    -324.6uA   -816.9uA   -269.6uA
1.2V      0A         0A         0A
[POWER_clamp]
|Voltage   I(typ)   I(min)   I(max)
-1.175V   127.9mA    151.5mA    114.3mA
-1.125V   95.1mA     119.3mA    81.28mA
-1.1V     80mA       104.1mA    66.45mA
-1.05V    53.45mA    76.24mA    42.06mA
-1.025V   42.52mA    63.79mA    33.25mA
-975mV    26.41mA    42.63mA    22.64mA
-925mV    17.53mA    27.24mA    17.96mA
-875mV    13.14mA    17.46mA    15.36mA
-800mV    9.702mA    10.06mA    12.29mA
-625mV    4.476mA    4.013mA    6.017mA
-350mV    147.7uA    296.5uA    176.7uA
1.2V      0A         0A         0A
[Ramp]
| variable   typ   min   max
dV/dt_r   0.458/1.722n   0.431/2.552n   0.462/1.111n
dV/dt_f   0.460/1.416n   0.442/2.272n   0.466/0.811n
R_load = 50.000
[Rising Waveform]
R_fixture= 50.000
V_fixture= 0.0
V_fixture_min= 0.0
V_fixture_max= 0.0
|time   V(typ)   V(min)   V(max)
0s        932.8nV    5.117uV    427.9nV
460ps     -3.105mV   -88.63uV   -8.701mV
663ps     1.822mV    -9.909mV   146mV
946ps     182.9mV    41.6mV     387mV
1.329ns   391.4mV    225.9mV    520.5mV
2.067ns   541.6mV    433.2mV    669.4mV
3.479ns   692.2mV    557.9mV    757.3mV
5.579ns   751.4mV    667.1mV    768.7mV
8.898ns   761.6mV    709.2mV    769.7mV
50ns      762.5mV    717.8mV    769.8mV
[Rising Waveform]
R_fixture= 50.000
V_fixture= 1.200
V_fixture_min= 1.160
V_fixture_max= 1.240
|time   V(typ)   V(min)   V(max)
0s        433.4mV    423.4mV    464.1mV
408ps     432.8mV    423.4mV    476mV
518ps     456.3mV    423mV      784.7mV
605ps     676.8mV    440.4mV    1.024V
701ps     941.4mV    617.2mV    1.145V
794ps     1.079V     855.3mV    1.197V
917ps     1.155V     1.044V     1.226V
1.118ns   1.191V     1.135V     1.238V
1.715ns   1.2V       1.16V      1.24V
50ns      1.2V       1.16V      1.24V
[Falling Waveform]
R_fixture= 50.000
V_fixture= 1.200
V_fixture_min= 1.160
V_fixture_max= 1.240
|time   V(typ)   V(min)   V(max)
0s        1.2V       1.16V      1.24V
1.285ns   1.201V     1.161V     1.217V
1.635ns   1.198V     1.161V     1.092V
2.107ns   1.158V     1.157V     806.6mV
2.707ns   1.006V     1.129V     551.4mV
3.966ns   591.9mV    930.6mV    481.6mV
5.176ns   480.4mV    664.3mV    470.4mV
5.993ns   460.2mV    553.4mV    467.4mV
9.366ns   437.7mV    447.2mV    464.4mV
50ns      433.4mV    423.4mV    464.1mV
[Falling Waveform]
R_fixture= 50.000
V_fixture= 0.0
V_fixture_min= 0.0
V_fixture_max= 0.0
|time   V(typ)   V(min)   V(max)
0s        762.5mV    717.8mV    769.7mV
420ps     764.9mV    718.7mV    746.2mV
462ps     761.9mV    720.2mV    665.7mV
522ps     731.3mV    719.6mV    426.4mV
597ps     559.5mV    701.5mV    218.8mV
686ps     275.8mV    586.7mV    102.9mV
786ps     119.7mV    326.9mV    45.96mV
932ps     38.24mV    102.6mV    15.24mV
1.161ns   7.648mV    18.96mV    4.155mV
50ns      933.8nV    5.121uV    429.5nV
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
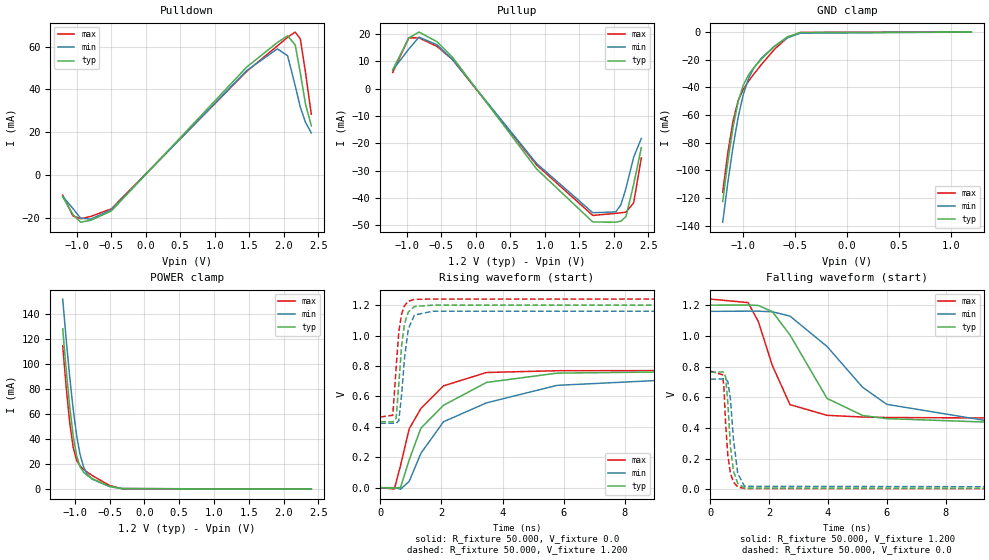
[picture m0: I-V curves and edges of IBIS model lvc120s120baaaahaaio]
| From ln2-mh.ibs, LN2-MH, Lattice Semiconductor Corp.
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|   Model lvc120s120baaaahaaio
[Model] lvc120s120baaaahaaio
| Clamp models do not include dynamic input termination. Please refer to
| the lvc120axxxbaaaahaain model for input termination.
Model_type I/O
Polarity   Non-Inverting
Enable   Active-Low
Vinl =  0.420V
Vinh =  0.780V
Vmeas =  0.600V
Cref =  0.0F
Rref =  1.000M
Vref =  0.0V
C_comp   2.000pF   1.500pF   2.500pF
[Temperature Range]   25.000   0.125k   -40.000
[Voltage Range]   1.200V   1.160V   1.240V
[C Comp Corner]
C_comp   2.000pF   1.500pF   2.500pF
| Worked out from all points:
|   slope of the pulldown table from 0 to 0.18 V, typ, clamps not added: 28.2 ohm
|   slope of the pullup table from 0 to 0.18 V, typ, clamps not added: 28.8 ohm
|   GND clamp passes 1 mA (typ) near -0.50 V on its own axis
|   POWER clamp passes 1 mA (typ) near -0.43 V on its own axis
|   rising waveform, R_fixture 50.000, V_fixture 0.0: 20-80 % time 1.72ns typ, 2.55ns min, 1.11ns max; typ from 0 V to 0.763 V
|   rising waveform, R_fixture 50.000, V_fixture 1.200: 20-80 % time 192ps typ, 204ps min, 178ps max; typ from 0.433 V to 1.2 V
|   falling waveform, R_fixture 50.000, V_fixture 1.200: 20-80 % time 1.41ns typ, 2.26ns min, 811ps max; typ from 1.2 V to 0.433 V
|   falling waveform, R_fixture 50.000, V_fixture 0.0: 20-80 % time 175ps typ, 198ps min, 162ps max; typ from 0.763 V to 0 V
[Pulldown]
|Voltage   I(typ)   I(min)   I(max)
-1.2V     -10.29mA   -10.11mA   -9.541mA
-1.052V   -18.64mA   -15.78mA   -19.21mA
-941mV    -22.19mA   -20.32mA   -20.6mA
-793mV    -21.3mA    -20.74mA   -19.49mA
-497mV    -16.98mA   -16.39mA   -15.97mA
1.464V    50.41mA    48.78mA    48.4mA
1.908V    61.95mA    58.95mA    60.32mA
2.056V    65.05mA    55.77mA    64.38mA
2.167V    60.79mA    41.64mA    66.8mA
2.241V    47.61mA    31.58mA    63.62mA
2.315V    33.16mA    24.63mA    47.99mA
2.4V      22.96mA    19.6mA     28.32mA
[Pullup]
|Voltage   I(typ)   I(min)   I(max)
-1.2V     6.849mA    6.78mA     5.874mA
-967mV    18.55mA    14.45mA    18.59mA
-819mV    20.67mA    18.83mA    18.55mA
-560mV    17.17mA    16.04mA    15.46mA
-338mV    11.58mA    10.78mA    10.71mA
883mV     -29.4mA    -27.4mA    -27.91mA
1.697V    -48.81mA   -45.43mA   -46.43mA
2.03V     -48.89mA   -45.12mA   -45.65mA
2.104V    -48.53mA   -42.54mA   -45.47mA
2.178V    -46.81mA   -36.49mA   -45.2mA
2.289V    -35.05mA   -25.14mA   -41.82mA
2.4V      -21.63mA   -18.24mA   -25.35mA
[GND_clamp]
|Voltage   I(typ)   I(min)   I(max)
-1.2V     -122.6mA   -137.6mA   -116mA
-1.15V    -93.41mA   -108.6mA   -87.01mA
-1.1V     -68.62mA   -82.86mA   -64.16mA
-1.05V    -50.02mA   -61.28mA   -49.51mA
-1V       -38.12mA   -44.82mA   -41.23mA
-950mV    -30.88mA   -33.5mA    -35.49mA
-900mV    -25.78mA   -26.06mA   -30.47mA
-825mV    -19.44mA   -18.76mA   -23.36mA
-700mV    -10.25mA   -10.24mA   -12.44mA
-575mV    -3.381mA   -4.102mA   -4.007mA
-450mV    -315.1uA   -796.4uA   -262uA
1.2V      0A         0A         0A
[POWER_clamp]
|Voltage   I(typ)   I(min)   I(max)
-1.175V   127.9mA    151.6mA    114.4mA
-1.125V   95.2mA     119.4mA    81.41mA
-1.075V   66.17mA    89.85mA    53.4mA
-1.025V   42.7mA     63.91mA    33.48mA
-975mV    26.64mA    42.78mA    22.93mA
-925mV    17.79mA    27.41mA    18.29mA
-875mV    13.42mA    17.66mA    15.69mA
-825mV    10.95mA    12.07mA    13.61mA
-750mV    8.323mA    7.791mA    10.74mA
-500mV    2.04mA     1.98mA     2.782mA
-325mV    310.3uA    373.2uA    366.8uA
2.4V      -105uA     -106.2uA   -106.1uA
[Ramp]
| variable   typ   min   max
dV/dt_r   0.458/1.722n   0.431/2.552n   0.462/1.111n
dV/dt_f   0.460/1.416n   0.442/2.272n   0.466/0.811n
R_load = 50.000
[Rising Waveform]
R_fixture= 50.000
V_fixture= 0.0
V_fixture_min= 0.0
V_fixture_max= 0.0
|time   V(typ)   V(min)   V(max)
0s        932.8nV    5.117uV    427.9nV
460ps     -3.105mV   -88.63uV   -8.701mV
663ps     1.822mV    -9.909mV   146mV
946ps     182.9mV    41.6mV     387mV
1.329ns   391.4mV    225.9mV    520.5mV
2.067ns   541.6mV    433.2mV    669.4mV
3.473ns   691.7mV    557.5mV    757.2mV
5.78ns    753mV      672.6mV    768.9mV
9.838ns   762.1mV    712.4mV    769.8mV
50ns      762.5mV    717.8mV    769.8mV
[Rising Waveform]
R_fixture= 50.000
V_fixture= 1.200
V_fixture_min= 1.160
V_fixture_max= 1.240
|time   V(typ)   V(min)   V(max)
0s        433.4mV    423.4mV    464.1mV
408ps     432.8mV    423.4mV    476mV
518ps     456.3mV    423mV      784.7mV
605ps     676.8mV    440.4mV    1.024V
701ps     941.4mV    617.2mV    1.145V
794ps     1.079V     855.3mV    1.197V
917ps     1.155V     1.044V     1.226V
1.118ns   1.191V     1.135V     1.238V
1.715ns   1.2V       1.16V      1.24V
50ns      1.2V       1.16V      1.24V
[Falling Waveform]
R_fixture= 50.000
V_fixture= 1.200
V_fixture_min= 1.160
V_fixture_max= 1.240
|time   V(typ)   V(min)   V(max)
0s        1.2V       1.16V      1.24V
1.285ns   1.201V     1.161V     1.217V
1.635ns   1.198V     1.161V     1.092V
2.107ns   1.158V     1.157V     806.6mV
2.707ns   1.006V     1.129V     551.4mV
3.966ns   591.9mV    930.6mV    481.6mV
5.176ns   480.4mV    664.3mV    470.4mV
5.993ns   460.2mV    553.4mV    467.4mV
9.366ns   437.7mV    447.2mV    464.4mV
50ns      433.4mV    423.4mV    464.1mV
[Falling Waveform]
R_fixture= 50.000
V_fixture= 0.0
V_fixture_min= 0.0
V_fixture_max= 0.0
|time   V(typ)   V(min)   V(max)
0s        762.5mV    717.8mV    769.7mV
420ps     764.9mV    718.7mV    746.2mV
462ps     761.9mV    720.2mV    665.7mV
522ps     731.3mV    719.6mV    426.4mV
597ps     559.5mV    701.5mV    218.8mV
686ps     275.8mV    586.7mV    102.9mV
786ps     119.7mV    326.9mV    45.96mV
932ps     38.24mV    102.6mV    15.24mV
1.161ns   7.648mV    18.96mV    4.155mV
50ns      933.8nV    5.121uV    429.5nV
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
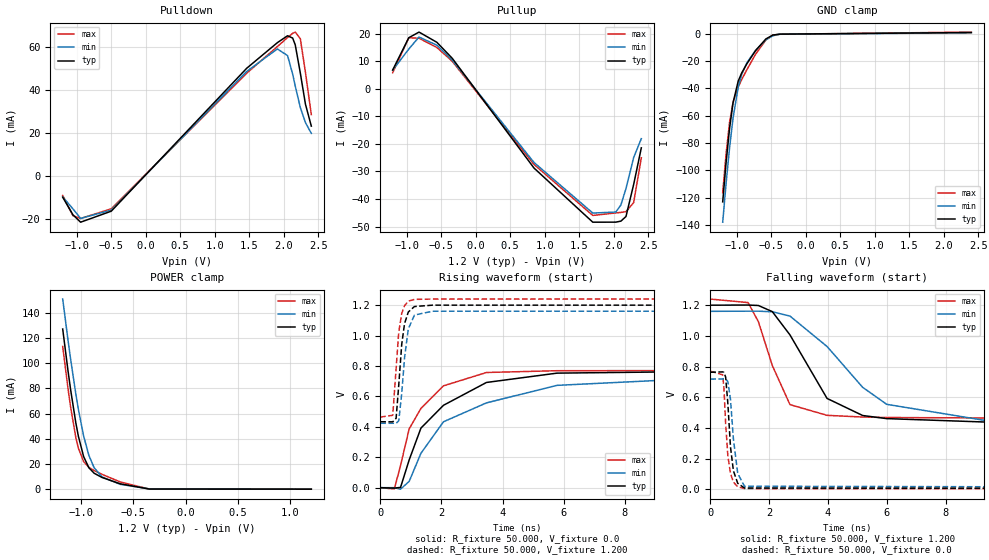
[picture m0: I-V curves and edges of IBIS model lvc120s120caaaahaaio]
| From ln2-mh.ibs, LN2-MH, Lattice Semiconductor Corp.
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|   Model lvc120s120caaaahaaio
[Model] lvc120s120caaaahaaio
| Clamp models do not include dynamic input termination. Please refer to
| the lvc120axxxcaaaahaain model for input termination.
Model_type I/O
Polarity   Non-Inverting
Enable   Active-Low
Vinl =  0.420V
Vinh =  0.780V
Vmeas =  0.600V
Cref =  0.0F
Rref =  1.000M
Vref =  0.0V
C_comp   2.000pF   1.500pF   2.500pF
[Temperature Range]   25.000   0.125k   -40.000
[Voltage Range]   1.200V   1.160V   1.240V
[C Comp Corner]
C_comp   2.000pF   1.500pF   2.500pF
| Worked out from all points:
|   slope of the pulldown table from 0 to 0.18 V, typ, clamps not added: 29 ohm
|   slope of the pullup table from 0 to 0.18 V, typ, clamps not added: 28.5 ohm
|   GND clamp passes 1 mA (typ) near -0.47 V on its own axis
|   POWER clamp passes 1 mA (typ) near -0.46 V on its own axis
|   rising waveform, R_fixture 50.000, V_fixture 0.0: 20-80 % time 1.72ns typ, 2.55ns min, 1.11ns max; typ from 0 V to 0.763 V
|   rising waveform, R_fixture 50.000, V_fixture 1.200: 20-80 % time 192ps typ, 204ps min, 178ps max; typ from 0.433 V to 1.2 V
|   falling waveform, R_fixture 50.000, V_fixture 1.200: 20-80 % time 1.41ns typ, 2.26ns min, 811ps max; typ from 1.2 V to 0.433 V
|   falling waveform, R_fixture 50.000, V_fixture 0.0: 20-80 % time 175ps typ, 198ps min, 162ps max; typ from 0.763 V to 0 V
[Pulldown]
|Voltage   I(typ)   I(min)   I(max)
-1.2V     -10.07mA   -9.928mA   -9.28mA
-1.052V   -18.25mA   -15.5mA    -18.68mA
-941mV    -21.7mA    -19.95mA   -19.98mA
-497mV    -16.58mA   -16.07mA   -15.47mA
1.464V    49.89mA    48.41mA    47.61mA
1.908V    61.8mA     58.9mA     59.98mA
2.056V    65.03mA    55.78mA    64.2mA
2.13V     63.95mA    47.17mA    66.15mA
2.167V    60.82mA    41.66mA    66.73mA
2.241V    47.64mA    31.6mA     63.61mA
2.315V    33.19mA    24.64mA    47.99mA
2.4V      22.98mA    19.62mA    28.33mA
[Pullup]
|Voltage   I(typ)   I(min)   I(max)
-1.2V     6.872mA    6.793mA    5.884mA
-967mV    18.58mA    14.47mA    18.56mA
-819mV    20.62mA    18.82mA    18.38mA
-560mV    16.9mA     15.86mA    15.02mA
-338mV    11.11mA    10.43mA    10.03mA
846mV     -28.75mA   -26.73mA   -27.43mA
1.697V    -48.41mA   -45.09mA   -45.96mA
2.03V     -48.39mA   -44.73mA   -45.05mA
2.104V    -48.03mA   -42.17mA   -44.86mA
2.178V    -46.34mA   -36.19mA   -44.58mA
2.289V    -34.72mA   -24.93mA   -41.28mA
2.4V      -21.41mA   -18.08mA   -25.04mA
[GND_clamp]
|Voltage   I(typ)   I(min)   I(max)
-1.2V     -123mA     -137.9mA   -116.3mA
-1.15V    -93.77mA   -109mA     -87.45mA
-1.1V     -69.04mA   -83.2mA    -64.7mA
-1.05V    -50.52mA   -61.66mA   -50.16mA
-975mV    -34.68mA   -39.02mA   -38.92mA
-925mV    -28.78mA   -29.88mA   -33.66mA
-850mV    -22.06mA   -21.38mA   -26.4mA
-725mV    -12.54mA   -12.25mA   -15.19mA
-575mV    -3.931mA   -4.562mA   -4.668mA
-475mV    -1.083mA   -1.617mA   -1.164mA
-375mV    -415.4uA   -497uA     -482.7uA
2.4V      768.5uA    596.7uA    1.09mA
[POWER_clamp]
|Voltage   I(typ)   I(min)   I(max)
-1.175V   127.2mA    151mA      113.4mA
-1.125V   94.42mA    118.8mA    80.34mA
-1.1V     79.34mA    103.6mA    65.54mA
-1.05V    52.82mA    75.75mA    41.2mA
-1.025V   41.91mA    63.3mA     32.44mA
-975mV    25.85mA    42.18mA    21.92mA
-925mV    17.02mA    26.81mA    17.31mA
-875mV    12.68mA    17.07mA    14.77mA
-800mV    9.315mA    9.719mA    11.8mA
-625mV    4.252mA    3.803mA    5.726mA
-350mV    125.8uA    261.6uA    148.8uA
1.2V      0A         0A         0A
[Ramp]
| variable   typ   min   max
dV/dt_r   0.458/1.722n   0.431/2.552n   0.462/1.111n
dV/dt_f   0.460/1.416n   0.442/2.272n   0.466/0.811n
R_load = 50.000
[Rising Waveform]
R_fixture= 50.000
V_fixture= 0.0
V_fixture_min= 0.0
V_fixture_max= 0.0
|time   V(typ)   V(min)   V(max)
0s        932.8nV    5.117uV    427.9nV
460ps     -3.105mV   -88.63uV   -8.701mV
663ps     1.822mV    -9.909mV   146mV
946ps     182.9mV    41.6mV     387mV
1.329ns   391.4mV    225.9mV    520.5mV
2.067ns   541.6mV    433.2mV    669.4mV
3.473ns   691.7mV    557.5mV    757.2mV
5.78ns    753mV      672.6mV    768.9mV
9.838ns   762.1mV    712.4mV    769.8mV
50ns      762.5mV    717.8mV    769.8mV
[Rising Waveform]
R_fixture= 50.000
V_fixture= 1.200
V_fixture_min= 1.160
V_fixture_max= 1.240
|time   V(typ)   V(min)   V(max)
0s        433.4mV    423.4mV    464.1mV
408ps     432.8mV    423.4mV    476mV
518ps     456.3mV    423mV      784.7mV
605ps     676.8mV    440.4mV    1.024V
701ps     941.4mV    617.2mV    1.145V
794ps     1.079V     855.3mV    1.197V
917ps     1.155V     1.044V     1.226V
1.118ns   1.191V     1.135V     1.238V
1.715ns   1.2V       1.16V      1.24V
50ns      1.2V       1.16V      1.24V
[Falling Waveform]
R_fixture= 50.000
V_fixture= 1.200
V_fixture_min= 1.160
V_fixture_max= 1.240
|time   V(typ)   V(min)   V(max)
0s        1.2V       1.16V      1.24V
1.285ns   1.201V     1.161V     1.217V
1.635ns   1.198V     1.161V     1.092V
2.107ns   1.158V     1.157V     806.6mV
2.707ns   1.006V     1.129V     551.4mV
3.966ns   591.9mV    930.6mV    481.6mV
5.176ns   480.4mV    664.3mV    470.4mV
5.993ns   460.2mV    553.4mV    467.4mV
9.366ns   437.7mV    447.2mV    464.4mV
50ns      433.4mV    423.4mV    464.1mV
[Falling Waveform]
R_fixture= 50.000
V_fixture= 0.0
V_fixture_min= 0.0
V_fixture_max= 0.0
|time   V(typ)   V(min)   V(max)
0s        762.5mV    717.8mV    769.7mV
420ps     764.9mV    718.7mV    746.2mV
462ps     761.9mV    720.2mV    665.7mV
522ps     731.3mV    719.6mV    426.4mV
597ps     559.5mV    701.5mV    218.8mV
686ps     275.8mV    586.7mV    102.9mV
786ps     119.7mV    326.9mV    45.96mV
932ps     38.24mV    102.6mV    15.24mV
1.161ns   7.648mV    18.96mV    4.155mV
50ns      933.8nV    5.121uV    429.5nV
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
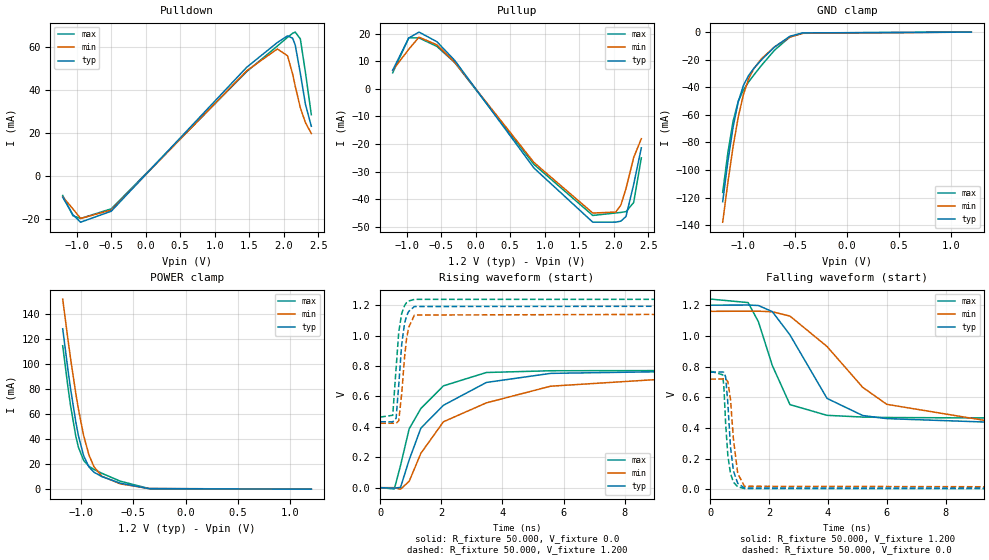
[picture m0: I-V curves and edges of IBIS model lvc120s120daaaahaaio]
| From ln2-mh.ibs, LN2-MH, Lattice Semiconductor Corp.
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|   Model lvc120s120daaaahaaio
[Model] lvc120s120daaaahaaio
| Clamp models do not include dynamic input termination. Please refer to
| the lvc120axxxdaaaahaain model for input termination.
Model_type I/O
Polarity   Non-Inverting
Enable   Active-Low
Vinl =  0.420V
Vinh =  0.780V
Vmeas =  0.600V
Cref =  0.0F
Rref =  1.000M
Vref =  0.0V
C_comp   2.000pF   1.500pF   2.500pF
[Temperature Range]   25.000   0.125k   -40.000
[Voltage Range]   1.200V   1.160V   1.240V
[C Comp Corner]
C_comp   2.000pF   1.500pF   2.500pF
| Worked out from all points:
|   slope of the pulldown table from 0 to 0.18 V, typ, clamps not added: 29 ohm
|   slope of the pullup table from 0 to 0.18 V, typ, clamps not added: 28.8 ohm
|   GND clamp passes 1 mA (typ) near -0.47 V on its own axis
|   POWER clamp passes 1 mA (typ) near -0.43 V on its own axis
|   rising waveform, R_fixture 50.000, V_fixture 0.0: 20-80 % time 1.72ns typ, 2.55ns min, 1.11ns max; typ from 0 V to 0.763 V
|   rising waveform, R_fixture 50.000, V_fixture 1.200: 20-80 % time 192ps typ, 204ps min, 178ps max; typ from 0.433 V to 1.2 V
|   falling waveform, R_fixture 50.000, V_fixture 1.200: 20-80 % time 1.41ns typ, 2.26ns min, 811ps max; typ from 1.2 V to 0.433 V
|   falling waveform, R_fixture 50.000, V_fixture 0.0: 20-80 % time 175ps typ, 198ps min, 162ps max; typ from 0.763 V to 0 V
[Pulldown]
|Voltage   I(typ)   I(min)   I(max)
-1.2V     -10.07mA   -9.928mA   -9.28mA
-1.052V   -18.25mA   -15.5mA    -18.68mA
-941mV    -21.7mA    -19.95mA   -19.98mA
-497mV    -16.58mA   -16.07mA   -15.47mA
1.464V    50.41mA    48.78mA    48.4mA
1.908V    61.95mA    58.95mA    60.32mA
2.056V    65.05mA    55.77mA    64.38mA
2.13V     63.92mA    47.15mA    66.26mA
2.167V    60.79mA    41.64mA    66.8mA
2.241V    47.61mA    31.58mA    63.62mA
2.315V    33.16mA    24.63mA    47.99mA
2.4V      22.96mA    19.6mA     28.32mA
[Pullup]
|Voltage   I(typ)   I(min)   I(max)
-1.2V     6.849mA    6.78mA     5.874mA
-967mV    18.55mA    14.45mA    18.59mA
-819mV    20.67mA    18.83mA    18.55mA
-560mV    17.17mA    16.04mA    15.46mA
-301mV    10.35mA    9.667mA    9.591mA
846mV     -28.75mA   -26.73mA   -27.43mA
1.697V    -48.41mA   -45.09mA   -45.96mA
2.03V     -48.39mA   -44.73mA   -45.05mA
2.104V    -48.03mA   -42.17mA   -44.86mA
2.178V    -46.34mA   -36.19mA   -44.58mA
2.289V    -34.72mA   -24.93mA   -41.28mA
2.4V      -21.41mA   -18.08mA   -25.04mA
[GND_clamp]
|Voltage   I(typ)   I(min)   I(max)
-1.2V     -123mA     -137.9mA   -116.3mA
-1.15V    -93.77mA   -109mA     -87.45mA
-1.1V     -69.04mA   -83.2mA    -64.7mA
-1.05V    -50.52mA   -61.66mA   -50.16mA
-1V       -38.68mA   -45.25mA   -41.93mA
-950mV    -31.48mA   -33.96mA   -36.21mA
-900mV    -26.38mA   -26.55mA   -31.19mA
-825mV    -20.04mA   -19.26mA   -24.07mA
-700mV    -10.83mA   -10.73mA   -13.14mA
-550mV    -2.967mA   -3.644mA   -3.468mA
-425mV    -588.2uA   -868.5uA   -635.3uA
1.2V      -845nA     5.241uA    -30.51uA
[POWER_clamp]
|Voltage   I(typ)   I(min)   I(max)
-1.175V   127.9mA    151.6mA    114.4mA
-1.125V   95.2mA     119.4mA    81.41mA
-1.1V     80.12mA    104.2mA    66.6mA
-1.05V    53.6mA     76.35mA    42.26mA
-1.025V   42.7mA     63.91mA    33.48mA
-975mV    26.64mA    42.78mA    22.93mA
-925mV    17.79mA    27.41mA    18.29mA
-875mV    13.42mA    17.66mA    15.69mA
-800mV    9.995mA    10.28mA    12.63mA
-625mV    4.774mA    4.24mA     6.369mA
-350mV    398.5uA    489.6uA    483.6uA
1.2V      0A         0A         49.13uA
[Ramp]
| variable   typ   min   max
dV/dt_r   0.458/1.722n   0.431/2.552n   0.462/1.111n
dV/dt_f   0.460/1.416n   0.442/2.272n   0.466/0.811n
R_load = 50.000
[Rising Waveform]
R_fixture= 50.000
V_fixture= 0.0
V_fixture_min= 0.0
V_fixture_max= 0.0
|time   V(typ)   V(min)   V(max)
0s        932.8nV    5.117uV    427.9nV
460ps     -3.105mV   -88.63uV   -8.701mV
663ps     1.822mV    -9.909mV   146mV
946ps     182.9mV    41.6mV     387mV
1.329ns   391.4mV    225.9mV    520.5mV
2.067ns   541.6mV    433.2mV    669.4mV
3.473ns   691.7mV    557.5mV    757.2mV
5.577ns   751.4mV    667.1mV    768.7mV
8.92ns    761.6mV    709.3mV    769.7mV
50ns      762.5mV    717.8mV    769.8mV
[Rising Waveform]
R_fixture= 50.000
V_fixture= 1.200
V_fixture_min= 1.160
V_fixture_max= 1.240
|time   V(typ)   V(min)   V(max)
0s        433.4mV    423.4mV    464.1mV
408ps     432.8mV    423.4mV    476mV
518ps     456.3mV    423mV      784.7mV
605ps     676.8mV    440.4mV    1.024V
701ps     941.4mV    617.2mV    1.145V
794ps     1.079V     855.3mV    1.197V
857ps     1.127V     974.6mV    1.216V
927ps     1.158V     1.052V     1.227V
1.119ns   1.191V     1.135V     1.238V
50ns      1.2V       1.16V      1.24V
[Falling Waveform]
R_fixture= 50.000
V_fixture= 1.200
V_fixture_min= 1.160
V_fixture_max= 1.240
|time   V(typ)   V(min)   V(max)
0s        1.2V       1.16V      1.24V
1.285ns   1.201V     1.161V     1.217V
1.635ns   1.198V     1.161V     1.092V
2.107ns   1.158V     1.157V     806.6mV
2.707ns   1.006V     1.129V     551.4mV
3.966ns   591.9mV    930.6mV    481.6mV
5.176ns   480.4mV    664.3mV    470.4mV
5.993ns   460.2mV    553.4mV    467.4mV
9.361ns   437.7mV    447.2mV    464.4mV
50ns      433.4mV    423.4mV    464.1mV
[Falling Waveform]
R_fixture= 50.000
V_fixture= 0.0
V_fixture_min= 0.0
V_fixture_max= 0.0
|time   V(typ)   V(min)   V(max)
0s        762.5mV    717.8mV    769.7mV
420ps     764.9mV    718.7mV    746.2mV
462ps     761.9mV    720.2mV    665.7mV
522ps     731.3mV    719.6mV    426.4mV
597ps     559.5mV    701.5mV    218.8mV
686ps     275.8mV    586.7mV    102.9mV
786ps     119.7mV    326.9mV    45.96mV
932ps     38.24mV    102.6mV    15.24mV
1.161ns   7.649mV    18.96mV    4.155mV
50ns      933.9nV    5.121uV    429.5nV
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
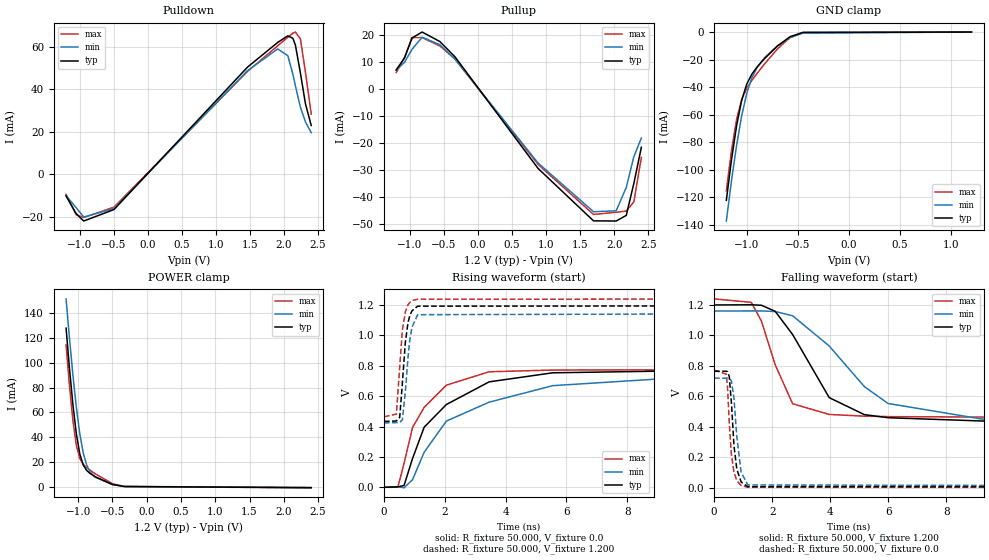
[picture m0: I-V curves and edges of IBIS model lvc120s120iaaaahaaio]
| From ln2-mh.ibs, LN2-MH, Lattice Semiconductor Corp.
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|   Model lvc120s120iaaaahaaio
[Model] lvc120s120iaaaahaaio
| Clamp models do not include dynamic input termination. Please refer to
| the lvc120axxxiaaaahaain model for input termination.
Model_type I/O
Polarity   Non-Inverting
Enable   Active-Low
Vinl =  0.420V
Vinh =  0.780V
Vmeas =  0.600V
Cref =  0.0F
Rref =  1.000M
Vref =  0.0V
C_comp   2.000pF   1.500pF   2.500pF
[Temperature Range]   25.000   0.125k   -40.000
[Voltage Range]   1.200V   1.160V   1.240V
[C Comp Corner]
C_comp   2.000pF   1.500pF   2.500pF
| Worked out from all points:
|   slope of the pulldown table from 0 to 0.18 V, typ, clamps not added: 28.4 ohm
|   slope of the pullup table from 0 to 0.18 V, typ, clamps not added: 28.5 ohm
|   GND clamp passes 1 mA (typ) near -0.50 V on its own axis
|   POWER clamp passes 1 mA (typ) near -0.44 V on its own axis
|   rising waveform, R_fixture 50.000, V_fixture 0.0: 20-80 % time 1.71ns typ, 2.54ns min, 1.1ns max; typ from 0 V to 0.765 V
|   rising waveform, R_fixture 50.000, V_fixture 1.200: 20-80 % time 188ps typ, 201ps min, 174ps max; typ from 0.433 V to 1.2 V
|   falling waveform, R_fixture 50.000, V_fixture 1.200: 20-80 % time 1.42ns typ, 2.26ns min, 811ps max; typ from 1.2 V to 0.433 V
|   falling waveform, R_fixture 50.000, V_fixture 0.0: 20-80 % time 175ps typ, 198ps min, 162ps max; typ from 0.765 V to 0 V
[Pulldown]
|Voltage   I(typ)   I(min)   I(max)
-1.2V     -10.22mA   -10.05mA   -9.458mA
-1.052V   -18.5mA    -15.68mA   -19.01mA
-941mV    -21.98mA   -20.16mA   -20.31mA
-497mV    -16.58mA   -16.07mA   -15.45mA
1.464V    50.53mA    48.88mA    48.52mA
1.908V    62.19mA    59.13mA    60.61mA
2.056V    65.29mA    55.93mA    64.67mA
2.13V     64.14mA    47.28mA    66.54mA
2.167V    60.99mA    41.75mA    67.08mA
2.241V    47.75mA    31.66mA    63.85mA
2.315V    33.26mA    24.69mA    48.13mA
2.4V      23.03mA    19.66mA    28.41mA
[Pullup]
|Voltage   I(typ)   I(min)   I(max)
-1.2V     6.935mA    6.851mA    5.966mA
-1.078V   11.4mA     9.77mA     11.47mA
-967mV    18.78mA    14.6mA     18.9mA
-819mV    20.96mA    19.05mA    18.9mA
-560mV    17.46mA    16.27mA    15.82mA
-338mV    11.82mA    10.96mA    11mA
883mV     -29.49mA   -27.49mA   -27.99mA
1.697V    -48.88mA   -45.5mA    -46.51mA
2.03V     -48.94mA   -45.17mA   -45.71mA
2.178V    -46.87mA   -36.54mA   -45.26mA
2.289V    -35.11mA   -25.18mA   -41.89mA
2.4V      -21.66mA   -18.26mA   -25.4mA
[GND_clamp]
|Voltage   I(typ)   I(min)   I(max)
-1.2V     -122.1mA   -137.1mA   -115.3mA
-1.15V    -92.88mA   -108.2mA   -86.34mA
-1.1V     -68.13mA   -82.44mA   -63.55mA
-1.05V    -49.58mA   -60.89mA   -48.98mA
-1V       -37.73mA   -44.48mA   -40.75mA
-950mV    -30.55mA   -33.19mA   -35.07mA
-900mV    -25.48mA   -25.79mA   -30.1mA
-825mV    -19.21mA   -18.55mA   -23.07mA
-700mV    -10.12mA   -10.12mA   -12.27mA
-575mV    -3.338mA   -4.053mA   -3.949mA
-450mV    -310.5uA   -787.2uA   -256.6uA
1.2V      0A         0A         0A
[POWER_clamp]
|Voltage   I(typ)   I(min)   I(max)
-1.175V   127.9mA    151.5mA    114.4mA
-1.125V   95.11mA    119.3mA    81.3mA
-1.075V   66.05mA    89.76mA    53.26mA
-1.025V   42.55mA    63.81mA    33.28mA
-975mV    26.45mA    42.66mA    22.68mA
-925mV    17.56mA    27.27mA    18.01mA
-875mV    13.18mA    17.5mA     15.4mA
-825mV    10.7mA     11.9mA     13.32mA
-750mV    8.076mA    7.611mA    10.45mA
-500mV    1.821mA    1.817mA    2.516mA
-325mV    164.5uA    258.7uA    189uA
2.4V      -731uA     -642.7uA   -887.3uA
[Ramp]
| variable   typ   min   max
dV/dt_r   0.459/1.715n   0.432/2.539n   0.464/1.105n
dV/dt_f   0.460/1.416n   0.442/2.265n   0.466/0.810n
R_load = 50.000
[Rising Waveform]
R_fixture= 50.000
V_fixture= 0.0
V_fixture_min= 0.0
V_fixture_max= 0.0
|time   V(typ)   V(min)   V(max)
0s        932.8nV    5.117uV    427.9nV
457ps     3.254mV    4.844mV    1.006mV
661ps     12.39mV    -3.292mV   158.1mV
942ps     190.9mV    51.42mV    394.7mV
1.322ns   395.9mV    231.1mV    526.4mV
2.052ns   544.9mV    435.9mV    672.3mV
3.456ns   694mV      560.3mV    760.3mV
5.545ns   753.5mV    668.9mV    771.8mV
8.903ns   763.9mV    711.5mV    772.8mV
50ns      764.8mV    720mV      772.9mV
[Rising Waveform]
R_fixture= 50.000
V_fixture= 1.200
V_fixture_min= 1.160
V_fixture_max= 1.240
|time   V(typ)   V(min)   V(max)
0s        433.4mV    423.4mV    464.1mV
408ps     436.6mV    426.2mV    481.5mV
518ps     460.8mV    426.4mV    794mV
605ps     683.7mV    444.2mV    1.034V
701ps     949.7mV    622.8mV    1.152V
791ps     1.084V     855.3mV    1.201V
848ps     1.128V     967.9mV    1.217V
921ps     1.161V     1.053V     1.229V
1.108ns   1.192V     1.136V     1.238V
50ns      1.2V       1.16V      1.24V
[Falling Waveform]
R_fixture= 50.000
V_fixture= 1.200
V_fixture_min= 1.160
V_fixture_max= 1.240
|time   V(typ)   V(min)   V(max)
0s        1.2V       1.16V      1.24V
1.282ns   1.201V     1.161V     1.217V
1.632ns   1.198V     1.161V     1.094V
2.106ns   1.158V     1.157V     807.2mV
2.706ns   1.006V     1.129V     551.6mV
3.966ns   591.9mV    930.6mV    481.6mV
5.176ns   480.4mV    664.3mV    470.4mV
5.992ns   460.2mV    553.5mV    467.4mV
9.361ns   437.7mV    447.2mV    464.4mV
50ns      433.4mV    423.4mV    464.1mV
[Falling Waveform]
R_fixture= 50.000
V_fixture= 0.0
V_fixture_min= 0.0
V_fixture_max= 0.0
|time   V(typ)   V(min)   V(max)
0s        764.8mV    720mV      772.8mV
420ps     765.2mV    719.3mV    746.3mV
462ps     762.1mV    720.5mV    665.7mV
522ps     731.3mV    719.7mV    426.3mV
597ps     559.5mV    701.5mV    218.7mV
686ps     275.7mV    586.7mV    102.9mV
782ps     123.8mV    336.8mV    47.43mV
931ps     38.53mV    103.4mV    15.35mV
1.161ns   7.648mV    18.97mV    4.155mV
50ns      933.9nV    5.121uV    429.5nV
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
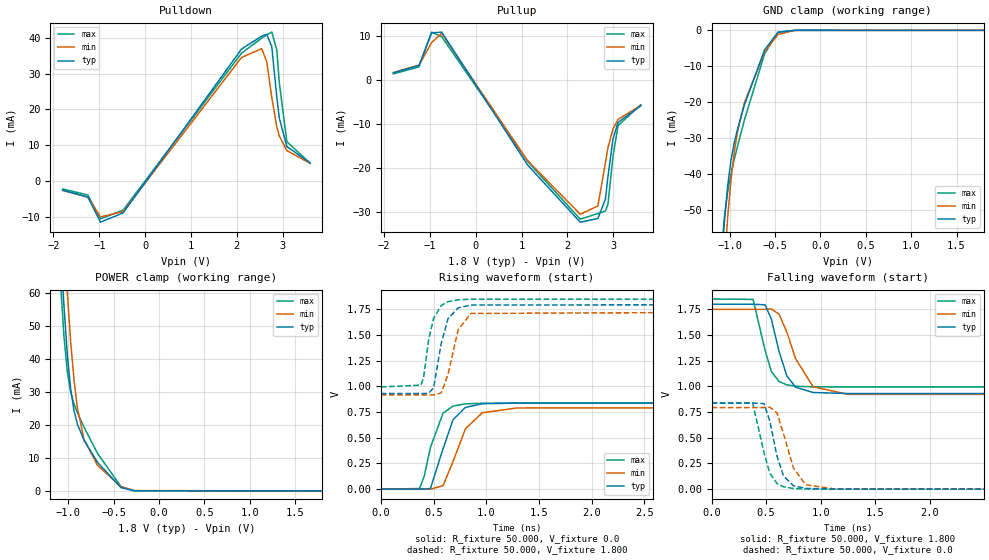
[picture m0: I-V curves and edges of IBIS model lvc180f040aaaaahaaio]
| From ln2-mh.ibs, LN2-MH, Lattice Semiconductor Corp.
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|   Model lvc180f040aaaaahaaio
[Model] lvc180f040aaaaahaaio
| Clamp models do not include dynamic input termination. Please refer to
| the lvc180axxxaaaaahaain model for input termination.
Model_type I/O
Polarity   Non-Inverting
Enable   Active-Low
Vinl =  0.630V
Vinh =  1.170V
Vmeas =  0.900V
Cref =  0.0F
Rref =  1.000M
Vref =  0.0V
C_comp   2.000pF   1.500pF   2.500pF
[Temperature Range]   25.000   0.125k   -40.000
[Voltage Range]   1.800V   1.750V   1.850V
[C Comp Corner]
C_comp   2.000pF   1.500pF   2.500pF
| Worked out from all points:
|   slope of the pulldown table from 0 to 0.27 V, typ, clamps not added: 53 ohm
|   slope of the pullup table from 0 to 0.27 V, typ, clamps not added: 55.2 ohm
|   GND clamp passes 1 mA (typ) near -0.49 V on its own axis
|   POWER clamp passes 1 mA (typ) near -0.42 V on its own axis
|   rising waveform, R_fixture 50.000, V_fixture 0.0: 20-80 % time 146ps typ, 183ps min, 127ps max; typ from 0 V to 0.838 V
|   rising waveform, R_fixture 50.000, V_fixture 1.800: 20-80 % time 96.4ps typ, 116ps min, 89.1ps max; typ from 0.93 V to 1.8 V
|   falling waveform, R_fixture 50.000, V_fixture 1.800: 20-80 % time 134ps typ, 182ps min, 110ps max; typ from 1.8 V to 0.93 V
|   falling waveform, R_fixture 50.000, V_fixture 0.0: 20-80 % time 111ps typ, 135ps min, 108ps max; typ from 0.838 V to 0 V
[Pulldown]
|Voltage   I(typ)   I(min)   I(max)
-1.8V     -2.482mA   -2.556mA   -2.152mA
-1.25V    -4.401mA   -4.43mA    -3.829mA
-975mV    -11.41mA   -9.932mA   -10.5mA
-480mV    -8.83mA    -8.472mA   -8.052mA
2.105V    36.85mA    34.5mA     35.7mA
2.545V    40.44mA    36.95mA    39.88mA
2.655V    40.95mA    33.36mA    40.84mA
2.765V    37.49mA    23.39mA    41.57mA
2.875V    23.42mA    15.13mA    36.57mA
2.93V     17.54mA    12.62mA    27.39mA
3.095V    9.665mA    8.527mA    11mA
3.6V      5.132mA    5.018mA    5.056mA
[Pullup]
|Voltage   I(typ)   I(min)   I(max)
-1.8V     1.616mA    1.727mA    1.404mA
-1.24V    3.334mA    3.394mA    2.99mA
-965mV    10.72mA    8.507mA    10.9mA
-745mV    10.91mA    10.64mA    9.88mA
1.125V    -19.24mA   -18.25mA   -18.43mA
2.28V     -32.33mA   -30.53mA   -31.64mA
2.665V    -31.5mA    -28.66mA   -30.37mA
2.83V     -27.08mA   -18.79mA   -29.79mA
2.885V    -21.95mA   -15.36mA   -28.28mA
2.995V    -13.39mA   -11.13mA   -17.39mA
3.105V    -9.651mA   -8.943mA   -10.37mA
3.6V      -5.85mA    -5.79mA    -5.624mA
[GND_clamp]
|Voltage   I(typ)   I(min)   I(max)
-1.8V     -570.9mA   -571.8mA   -572.9mA
-1.097V   -67.54mA   -81.64mA   -63.35mA
-1.06V    -53.45mA   -65.42mA   -52.13mA
-1.023V   -43.13mA   -51.95mA   -44.86mA
-986mV    -36.04mA   -41.41mA   -39.83mA
-949mV    -31.06mA   -33.56mA   -35.72mA
-912mV    -27.18mA   -27.83mA   -31.97mA
-838mV    -20.73mA   -20.06mA   -24.86mA
-616mV    -5.403mA   -5.958mA   -6.517mA
-468mV    -530.3uA   -1.122mA   -495.6uA
-283mV    -1.808uA   -19.61uA   -457.7nA
1.8V      0A         0A         0A
[POWER_clamp]
|Voltage   I(typ)   I(min)   I(max)
-1.789V   617.6mA    624.8mA    616.1mA
-1.086V   74.43mA    97.5mA     62.76mA
-1.049V   55.98mA    77.5mA     46.8mA
-1.012V   41.32mA    59.89mA    36.12mA
-975mV    30.91mA    45.13mA    29.96mA
-938mV    24.29mA    33.57mA    26.33mA
-901mV    20.21mA    25.16mA    23.7mA
-827mV    15.35mA    15.5mA     19.29mA
-679mV    8.657mA    7.724mA    11.36mA
-420mV    977.9uA    1.256mA    1.313mA
-272mV    22.92uA    106.7uA    14.08uA
1.8V      0A         0A         0A
[Ramp]
| variable   typ   min   max
dV/dt_r   0.503/0.146n   0.476/0.184n   0.502/0.127n
dV/dt_f   0.522/0.134n   0.500/0.182n   0.513/0.110n
R_load = 50.000
[Rising Waveform]
R_fixture= 50.000
V_fixture= 0.0
V_fixture_min= 0.0
V_fixture_max= 0.0
|time   V(typ)   V(min)   V(max)
0s        2.714uV    13.81uV    1.234uV
366ps     75.47uV    67.19uV    5.894mV
411ps     -399.7uV   81.82uV    126mV
470ps     7.095mV    -226.4uV   407.5mV
590ps     393.5mV    34.18mV    740.5mV
684ps     674.3mV    266.8mV    808.1mV
802ps     795.6mV    586.9mV    830.3mV
963ps     830.6mV    743.6mV    836mV
1.292ns   837.9mV    790mV      837mV
10ns      838.3mV    793.9mV    837.1mV
[Rising Waveform]
R_fixture= 50.000
V_fixture= 1.800
V_fixture_min= 1.750
V_fixture_max= 1.850
|time   V(typ)   V(min)   V(max)
0s        930.2mV    916.2mV    994.9mV
380ps     930.2mV    916.3mV    1.012V
405ps     930mV      916.3mV    1.089V
454ps     933.2mV    916mV      1.46V
500ps     987.4mV    916.6mV    1.663V
573ps     1.422V     937.4mV    1.788V
637ps     1.659V     1.117V     1.825V
733ps     1.764V     1.55V      1.843V
853ps     1.792V     1.71V      1.848V
10ns      1.8V       1.75V      1.85V
[Falling Waveform]
R_fixture= 50.000
V_fixture= 1.800
V_fixture_min= 1.750
V_fixture_max= 1.850
|time   V(typ)   V(min)   V(max)
0s        1.8V       1.75V      1.85V
380ps     1.8V       1.75V      1.847V
490ps     1.794V     1.751V     1.351V
547ps     1.657V     1.754V     1.147V
619ps     1.338V     1.703V     1.047V
690ps     1.102V     1.528V     1.015V
770ps     992.9mV    1.27V      1.002V
930ps     940.6mV    997.3mV    995.9mV
1.248ns   930.9mV    922.8mV    994.9mV
10ns      930.2mV    916.2mV    994.9mV
[Falling Waveform]
R_fixture= 50.000
V_fixture= 0.0
V_fixture_min= 0.0
V_fixture_max= 0.0
|time   V(typ)   V(min)   V(max)
0s        838.2mV    793.9mV    837mV
377ps     838.1mV    793.9mV    836.5mV
481ps     832.5mV    794.9mV    352.8mV
533ps     664.5mV    798.2mV    156.6mV
600ps     318.9mV    741.1mV    54.81mV
659ps     129.4mV    539.5mV    23.14mV
750ps     33.23mV    207.2mV    6.672mV
862ps     7.614mV    43.17mV    1.665mV
1.13ns    503.2uV    2.182mV    126.1uV
10ns      2.824uV    13.96uV    1.322uV
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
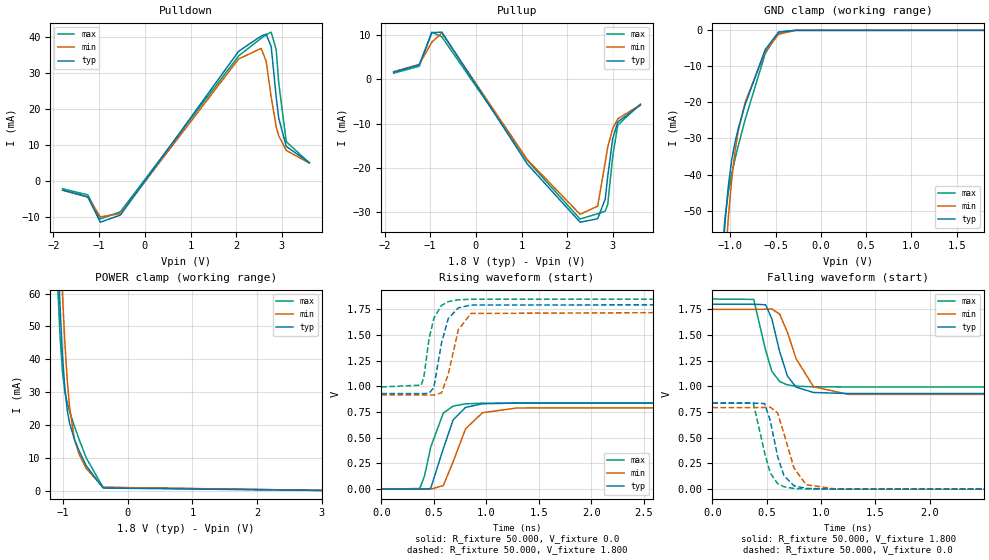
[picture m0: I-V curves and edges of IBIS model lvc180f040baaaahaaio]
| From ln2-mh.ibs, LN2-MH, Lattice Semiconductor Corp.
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|   Model lvc180f040baaaahaaio
[Model] lvc180f040baaaahaaio
| Clamp models do not include dynamic input termination. Please refer to
| the lvc180axxxbaaaahaain model for input termination.
Model_type I/O
Polarity   Non-Inverting
Enable   Active-Low
Vinl =  0.630V
Vinh =  1.170V
Vmeas =  0.900V
Cref =  0.0F
Rref =  1.000M
Vref =  0.0V
C_comp   2.000pF   1.500pF   2.500pF
[Temperature Range]   25.000   0.125k   -40.000
[Voltage Range]   1.800V   1.750V   1.850V
[C Comp Corner]
C_comp   2.000pF   1.500pF   2.500pF
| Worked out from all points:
|   slope of the pulldown table from 0 to 0.27 V, typ, clamps not added: 53 ohm
|   slope of the pullup table from 0 to 0.27 V, typ, clamps not added: 56.4 ohm
|   GND clamp passes 1 mA (typ) near -0.50 V on its own axis
|   POWER clamp passes 1 mA (typ) near -0.40 V on its own axis
|   rising waveform, R_fixture 50.000, V_fixture 0.0: 20-80 % time 146ps typ, 183ps min, 127ps max; typ from 0 V to 0.838 V
|   rising waveform, R_fixture 50.000, V_fixture 1.800: 20-80 % time 96.4ps typ, 116ps min, 89.1ps max; typ from 0.93 V to 1.8 V
|   falling waveform, R_fixture 50.000, V_fixture 1.800: 20-80 % time 134ps typ, 182ps min, 110ps max; typ from 1.8 V to 0.93 V
|   falling waveform, R_fixture 50.000, V_fixture 0.0: 20-80 % time 111ps typ, 135ps min, 108ps max; typ from 0.838 V to 0 V
[Pulldown]
|Voltage   I(typ)   I(min)   I(max)
-1.8V     -2.478mA   -2.551mA   -2.148mA
-1.25V    -4.394mA   -4.422mA   -3.822mA
-975mV    -11.39mA   -9.91mA    -10.48mA
-535mV    -9.409mA   -9.028mA   -8.507mA
2.05V     35.9mA     33.78mA    34.63mA
2.545V    40.14mA    36.73mA    39.53mA
2.655V    40.66mA    33.17mA    40.5mA
2.765V    37.25mA    23.26mA    41.24mA
2.875V    23.27mA    15.04mA    36.32mA
2.93V     17.43mA    12.54mA    27.21mA
3.095V    9.592mA    8.468mA    10.92mA
3.6V      5.086mA    4.976mA    5.008mA
[Pullup]
|Voltage   I(typ)   I(min)   I(max)
-1.8V     1.57mA     1.685mA    1.357mA
-1.24V    3.252mA    3.325mA    2.904mA
-965mV    10.47mA    8.347mA    10.59mA
-745mV    10.61mA    10.41mA    9.532mA
1.125V    -19.13mA   -18.14mA   -18.32mA
2.28V     -32.24mA   -30.46mA   -31.53mA
2.665V    -31.47mA   -28.64mA   -30.34mA
2.83V     -27.06mA   -18.77mA   -29.77mA
2.885V    -21.93mA   -15.35mA   -28.26mA
2.995V    -13.38mA   -11.12mA   -17.38mA
3.105V    -9.645mA   -8.936mA   -10.36mA
3.6V      -5.846mA   -5.785mA   -5.62mA
[GND_clamp]
|Voltage   I(typ)   I(min)   I(max)
-1.8V     -570.8mA   -571.7mA   -572.8mA
-1.097V   -67.45mA   -81.54mA   -63.25mA
-1.06V    -53.36mA   -65.33mA   -52.04mA
-1.023V   -43.04mA   -51.86mA   -44.77mA
-986mV    -35.95mA   -41.32mA   -39.74mA
-949mV    -30.97mA   -33.48mA   -35.64mA
-912mV    -27.1mA    -27.74mA   -31.88mA
-838mV    -20.66mA   -19.98mA   -24.78mA
-616mV    -5.345mA   -5.898mA   -6.456mA
-468mV    -515.9uA   -1.096mA   -482.9uA
-283mV    -1.482uA   -17.52uA   -322.5nA
1.8V      0A         0A         0A
[POWER_clamp]
|Voltage   I(typ)   I(min)   I(max)
-1.789V   617.6mA    624.8mA    616.1mA
-1.086V   74.57mA    97.6mA     62.94mA
-1.049V   56.15mA    77.62mA    47.03mA
-1.012V   41.52mA    60.02mA    36.39mA
-975mV    31.15mA    45.29mA    30.27mA
-938mV    24.56mA    33.75mA    26.65mA
-901mV    20.5mA     25.36mA    24.04mA
-827mV    15.64mA    15.72mA    19.63mA
-753mV    12.1mA     11mA       15.55mA
-642mV    7.512mA    6.704mA    9.896mA
-383mV    772.8uA    998.1uA    969uA
3.6V      -108.1uA   -110.5uA   -109.2uA
[Ramp]
| variable   typ   min   max
dV/dt_r   0.503/0.146n   0.476/0.184n   0.502/0.127n
dV/dt_f   0.522/0.134n   0.500/0.182n   0.513/0.110n
R_load = 50.000
[Rising Waveform]
R_fixture= 50.000
V_fixture= 0.0
V_fixture_min= 0.0
V_fixture_max= 0.0
|time   V(typ)   V(min)   V(max)
0s        2.714uV    13.81uV    1.234uV
366ps     75.47uV    67.19uV    5.894mV
411ps     -399.7uV   81.82uV    126mV
470ps     7.095mV    -226.4uV   407.5mV
590ps     393.5mV    34.18mV    740.5mV
684ps     674.3mV    266.8mV    808.1mV
802ps     795.6mV    586.9mV    830.3mV
963ps     830.6mV    743.6mV    836mV
1.292ns   837.9mV    790mV      837mV
10ns      838.3mV    793.9mV    837.1mV
[Rising Waveform]
R_fixture= 50.000
V_fixture= 1.800
V_fixture_min= 1.750
V_fixture_max= 1.850
|time   V(typ)   V(min)   V(max)
0s        930.2mV    916.2mV    994.9mV
380ps     930.2mV    916.3mV    1.012V
405ps     930mV      916.3mV    1.089V
454ps     933.2mV    916mV      1.46V
500ps     987.4mV    916.6mV    1.663V
573ps     1.422V     937.4mV    1.788V
637ps     1.659V     1.117V     1.825V
733ps     1.764V     1.55V      1.843V
853ps     1.792V     1.71V      1.848V
10ns      1.8V       1.75V      1.85V
[Falling Waveform]
R_fixture= 50.000
V_fixture= 1.800
V_fixture_min= 1.750
V_fixture_max= 1.850
|time   V(typ)   V(min)   V(max)
0s        1.8V       1.75V      1.85V
380ps     1.8V       1.75V      1.847V
490ps     1.794V     1.751V     1.351V
547ps     1.657V     1.754V     1.147V
619ps     1.338V     1.703V     1.047V
690ps     1.102V     1.528V     1.015V
770ps     992.9mV    1.27V      1.002V
930ps     940.6mV    997.3mV    995.9mV
1.248ns   930.9mV    922.8mV    994.9mV
10ns      930.2mV    916.2mV    994.9mV
[Falling Waveform]
R_fixture= 50.000
V_fixture= 0.0
V_fixture_min= 0.0
V_fixture_max= 0.0
|time   V(typ)   V(min)   V(max)
0s        838.2mV    793.9mV    837mV
377ps     838.1mV    793.9mV    836.5mV
481ps     832.5mV    794.9mV    352.8mV
533ps     664.5mV    798.2mV    156.6mV
600ps     318.9mV    741.1mV    54.81mV
659ps     129.4mV    539.5mV    23.14mV
750ps     33.23mV    207.2mV    6.672mV
862ps     7.614mV    43.17mV    1.665mV
1.13ns    503.2uV    2.182mV    126.1uV
10ns      2.824uV    13.96uV    1.322uV
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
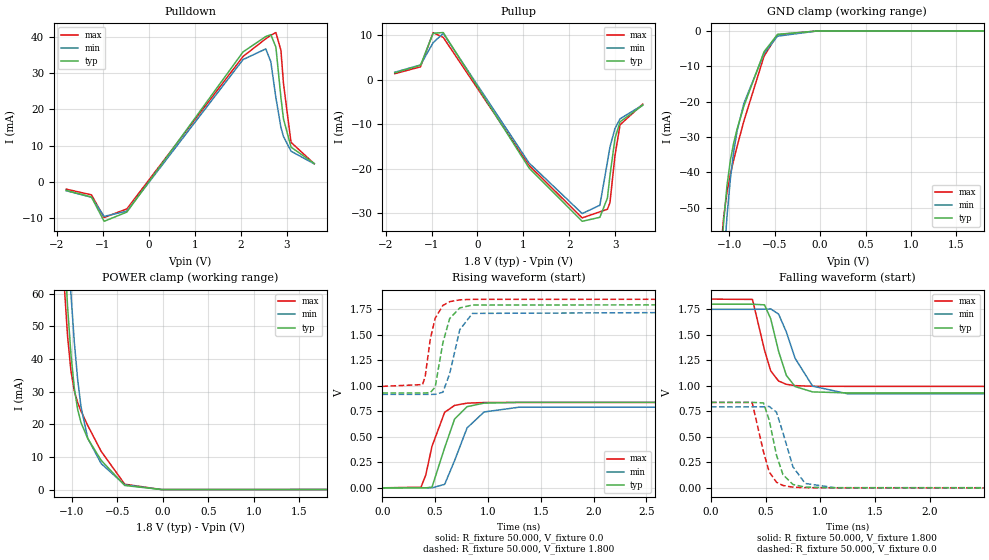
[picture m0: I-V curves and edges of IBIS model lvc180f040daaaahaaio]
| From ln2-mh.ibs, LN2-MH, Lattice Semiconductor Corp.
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|   Model lvc180f040daaaahaaio
[Model] lvc180f040daaaahaaio
| Clamp models do not include dynamic input termination. Please refer to
| the lvc180axxxdaaaahaain model for input termination.
Model_type I/O
Polarity   Non-Inverting
Enable   Active-Low
Vinl =  0.630V
Vinh =  1.170V
Vmeas =  0.900V
Cref =  0.0F
Rref =  1.000M
Vref =  0.0V
C_comp   2.000pF   1.500pF   2.500pF
[Temperature Range]   25.000   0.125k   -40.000
[Voltage Range]   1.800V   1.750V   1.850V
[C Comp Corner]
C_comp   2.000pF   1.500pF   2.500pF
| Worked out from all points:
|   slope of the pulldown table from 0 to 0.27 V, typ, clamps not added: 56 ohm
|   slope of the pullup table from 0 to 0.27 V, typ, clamps not added: 56.4 ohm
|   GND clamp passes 1 mA (typ) near -0.47 V on its own axis
|   POWER clamp passes 1 mA (typ) near -0.40 V on its own axis
|   rising waveform, R_fixture 50.000, V_fixture 0.0: 20-80 % time 146ps typ, 183ps min, 127ps max; typ from 0 V to 0.838 V
|   rising waveform, R_fixture 50.000, V_fixture 1.800: 20-80 % time 96.4ps typ, 116ps min, 89.1ps max; typ from 0.93 V to 1.8 V
|   falling waveform, R_fixture 50.000, V_fixture 1.800: 20-80 % time 134ps typ, 182ps min, 110ps max; typ from 1.8 V to 0.93 V
|   falling waveform, R_fixture 50.000, V_fixture 0.0: 20-80 % time 111ps typ, 135ps min, 108ps max; typ from 0.838 V to 0 V
[Pulldown]
|Voltage   I(typ)   I(min)   I(max)
-1.8V     -2.356mA   -2.442mA   -2.008mA
-1.25V    -4.196mA   -4.251mA   -3.59mA
-975mV    -10.89mA   -9.547mA   -9.847mA
-480mV    -8.346mA   -8.075mA   -7.463mA
2.05V     35.9mA     33.78mA    34.63mA
2.545V    40.14mA    36.73mA    39.53mA
2.655V    40.66mA    33.17mA    40.5mA
2.765V    37.25mA    23.26mA    41.24mA
2.875V    23.27mA    15.04mA    36.32mA
2.93V     17.43mA    12.54mA    27.21mA
3.095V    9.592mA    8.468mA    10.92mA
3.6V      5.086mA    4.976mA    5.008mA
[Pullup]
|Voltage   I(typ)   I(min)   I(max)
-1.8V     1.57mA     1.685mA    1.357mA
-1.24V    3.252mA    3.325mA    2.904mA
-965mV    10.47mA    8.347mA    10.59mA
-745mV    10.61mA    10.41mA    9.532mA
1.125V    -19.87mA   -18.74mA   -19.28mA
2.28V     -31.85mA   -30.11mA   -31.09mA
2.665V    -30.95mA   -28.24mA   -29.72mA
2.83V     -26.62mA   -18.51mA   -29.14mA
2.885V    -21.58mA   -15.13mA   -27.67mA
2.995V    -13.15mA   -10.95mA   -17.03mA
3.105V    -9.467mA   -8.79mA    -10.13mA
3.6V      -5.724mA   -5.679mA   -5.477mA
[GND_clamp]
|Voltage   I(typ)   I(min)   I(max)
-1.8V     -571mA     -571.9mA   -573mA
-1.097V   -67.89mA   -81.9mA    -63.82mA
-1.06V    -53.86mA   -65.72mA   -52.69mA
-1.023V   -43.6mA    -52.29mA   -45.48mA
-986mV    -36.55mA   -41.78mA   -40.47mA
-949mV    -31.59mA   -33.97mA   -36.38mA
-912mV    -27.73mA   -28.25mA   -32.63mA
-838mV    -21.28mA   -20.51mA   -25.51mA
-616mV    -5.929mA   -6.389mA   -7.151mA
-468mV    -1.006mA   -1.514mA   -1.077mA
-24mV     -25.08uA   -21.99uA   -30.46uA
1.8V      -83.5nA    0A         -36.66uA
[POWER_clamp]
|Voltage   I(typ)   I(min)   I(max)
-1.789V   617.6mA    624.8mA    616.1mA
-1.086V   74.57mA    97.6mA     62.94mA
-1.049V   56.15mA    77.62mA    47.03mA
-1.012V   41.52mA    60.02mA    36.39mA
-975mV    31.15mA    45.29mA    30.27mA
-938mV    24.56mA    33.75mA    26.65mA
-901mV    20.5mA     25.36mA    24.04mA
-827mV    15.64mA    15.72mA    19.63mA
-679mV    8.958mA    7.957mA    11.71mA
-420mV    1.258mA    1.471mA    1.65mA
-13mV     8.76uA     8.311uA    10.26uA
1.8V      0A         0A         63.06uA
[Ramp]
| variable   typ   min   max
dV/dt_r   0.503/0.146n   0.476/0.184n   0.502/0.127n
dV/dt_f   0.522/0.134n   0.500/0.182n   0.513/0.110n
R_load = 50.000
[Rising Waveform]
R_fixture= 50.000
V_fixture= 0.0
V_fixture_min= 0.0
V_fixture_max= 0.0
|time   V(typ)   V(min)   V(max)
0s        2.714uV    13.81uV    1.234uV
366ps     75.47uV    67.19uV    5.894mV
411ps     -399.7uV   81.82uV    126mV
470ps     7.095mV    -226.4uV   407.5mV
590ps     393.5mV    34.18mV    740.5mV
684ps     674.3mV    266.8mV    808.1mV
802ps     795.6mV    586.9mV    830.3mV
963ps     830.6mV    743.6mV    836mV
1.292ns   837.9mV    790mV      837mV
10ns      838.3mV    793.9mV    837.1mV
[Rising Waveform]
R_fixture= 50.000
V_fixture= 1.800
V_fixture_min= 1.750
V_fixture_max= 1.850
|time   V(typ)   V(min)   V(max)
0s        930.2mV    916.2mV    994.9mV
380ps     930.2mV    916.3mV    1.012V
405ps     930mV      916.3mV    1.089V
454ps     933.2mV    916mV      1.46V
500ps     987.4mV    916.6mV    1.663V
573ps     1.422V     937.4mV    1.788V
637ps     1.659V     1.117V     1.825V
733ps     1.764V     1.55V      1.843V
853ps     1.792V     1.71V      1.848V
10ns      1.8V       1.75V      1.85V
[Falling Waveform]
R_fixture= 50.000
V_fixture= 1.800
V_fixture_min= 1.750
V_fixture_max= 1.850
|time   V(typ)   V(min)   V(max)
0s        1.8V       1.75V      1.85V
380ps     1.8V       1.75V      1.847V
490ps     1.794V     1.751V     1.351V
547ps     1.657V     1.754V     1.147V
619ps     1.338V     1.703V     1.047V
690ps     1.102V     1.528V     1.015V
770ps     992.9mV    1.27V      1.002V
930ps     940.6mV    997.3mV    995.9mV
1.248ns   930.9mV    922.8mV    994.9mV
10ns      930.2mV    916.2mV    994.9mV
[Falling Waveform]
R_fixture= 50.000
V_fixture= 0.0
V_fixture_min= 0.0
V_fixture_max= 0.0
|time   V(typ)   V(min)   V(max)
0s        838.2mV    793.9mV    837mV
377ps     838.1mV    793.9mV    836.5mV
481ps     832.5mV    794.9mV    352.8mV
533ps     664.5mV    798.2mV    156.6mV
600ps     318.9mV    741.1mV    54.81mV
659ps     129.4mV    539.5mV    23.14mV
750ps     33.23mV    207.2mV    6.672mV
862ps     7.614mV    43.17mV    1.665mV
1.13ns    503.2uV    2.182mV    126.1uV
10ns      2.824uV    13.96uV    1.322uV
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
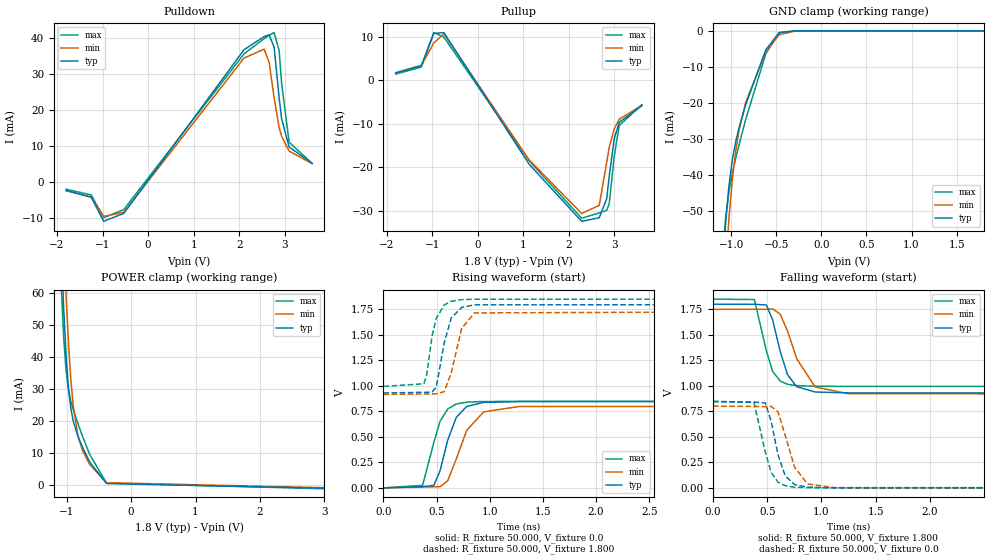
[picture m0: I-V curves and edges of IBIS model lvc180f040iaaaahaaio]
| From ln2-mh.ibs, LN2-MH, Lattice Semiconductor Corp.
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|   Model lvc180f040iaaaahaaio
[Model] lvc180f040iaaaahaaio
| Clamp models do not include dynamic input termination. Please refer to
| the lvc180axxxiaaaahaain model for input termination.
Model_type I/O
Polarity   Non-Inverting
Enable   Active-Low
Vinl =  0.630V
Vinh =  1.170V
Vmeas =  0.900V
Cref =  0.0F
Rref =  1.000M
Vref =  0.0V
C_comp   2.000pF   1.500pF   2.500pF
[Temperature Range]   25.000   0.125k   -40.000
[Voltage Range]   1.800V   1.750V   1.850V
[C Comp Corner]
C_comp   2.000pF   1.500pF   2.500pF
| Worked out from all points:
|   slope of the pulldown table from 0 to 0.27 V, typ, clamps not added: 53.9 ohm
|   slope of the pullup table from 0 to 0.27 V, typ, clamps not added: 55.3 ohm
|   GND clamp passes 1 mA (typ) near -0.50 V on its own axis
|   POWER clamp passes 1 mA (typ) near -0.41 V on its own axis
|   rising waveform, R_fixture 50.000, V_fixture 0.0: 20-80 % time 145ps typ, 182ps min, 125ps max; typ from 0 V to 0.846 V
|   rising waveform, R_fixture 50.000, V_fixture 1.800: 20-80 % time 95.1ps typ, 115ps min, 87.2ps max; typ from 0.93 V to 1.8 V
|   falling waveform, R_fixture 50.000, V_fixture 1.800: 20-80 % time 134ps typ, 182ps min, 110ps max; typ from 1.8 V to 0.93 V
|   falling waveform, R_fixture 50.000, V_fixture 0.0: 20-80 % time 112ps typ, 136ps min, 108ps max; typ from 0.846 V to 0 V
[Pulldown]
|Voltage   I(typ)   I(min)   I(max)
-1.8V     -2.429mA   -2.505mA   -2.09mA
-1.25V    -4.291mA   -4.331mA   -3.697mA
-975mV    -11.03mA   -9.654mA   -10mA
-535mV    -8.824mA   -8.548mA   -7.766mA
2.105V    36.76mA    34.43mA    35.61mA
2.545V    40.39mA    36.91mA    39.82mA
2.655V    40.91mA    33.33mA    40.79mA
2.765V    37.46mA    23.37mA    41.53mA
2.875V    23.4mA     15.11mA    36.54mA
2.93V     17.53mA    12.6mA     27.37mA
3.095V    9.655mA    8.517mA    10.99mA
3.6V      5.126mA    5.011mA    5.05mA
[Pullup]
|Voltage   I(typ)   I(min)   I(max)
-1.8V     1.616mA    1.727mA    1.404mA
-1.24V    3.334mA    3.394mA    2.991mA
-965mV    10.72mA    8.508mA    10.9mA
-745mV    10.91mA    10.64mA    9.881mA
1.125V    -19.23mA   -18.24mA   -18.42mA
2.28V     -32.33mA   -30.54mA   -31.63mA
2.665V    -31.52mA   -28.69mA   -30.4mA
2.83V     -27.13mA   -18.82mA   -29.82mA
2.885V    -22mA      -15.38mA   -28.33mA
2.995V    -13.41mA   -11.14mA   -17.44mA
3.105V    -9.66mA    -8.948mA   -10.38mA
3.6V      -5.851mA   -5.791mA   -5.625mA
[GND_clamp]
|Voltage   I(typ)   I(min)   I(max)
-1.8V     -569.8mA   -570.8mA   -571.6mA
-1.097V   -66.86mA   -81.02mA   -62.54mA
-1.06V    -52.83mA   -64.84mA   -51.42mA
-1.023V   -42.57mA   -51.42mA   -44.23mA
-986mV    -35.54mA   -40.92mA   -39.25mA
-949mV    -30.61mA   -33.13mA   -35.19mA
-912mV    -26.78mA   -27.43mA   -31.48mA
-838mV    -20.4mA    -19.75mA   -24.45mA
-616mV    -5.27mA    -5.819mA   -6.352mA
-468mV    -506.6uA   -1.081mA   -470.6uA
-283mV    -1.427uA   -17.24uA   -284.7nA
1.8V      0A         0A         0A
[POWER_clamp]
|Voltage   I(typ)   I(min)   I(max)
-1.789V   617.6mA    624.8mA    616.1mA
-1.086V   74.45mA    97.52mA    62.79mA
-1.049V   56mA       77.52mA    46.83mA
-1.012V   41.34mA    59.91mA    36.16mA
-975mV    30.94mA    45.16mA    30mA
-938mV    24.33mA    33.6mA     26.37mA
-901mV    20.25mA    25.2mA     23.75mA
-827mV    15.39mA    15.54mA    19.34mA
-753mV    11.85mA    10.81mA    15.26mA
-642mV    7.266mA    6.521mA    9.605mA
-383mV    595.8uA    860.9uA    753.9uA
3.6V      -1.113mA   -985.8uA   -1.346mA
[Ramp]
| variable   typ   min   max
dV/dt_r   0.508/0.145n   0.481/0.182n   0.508/0.125n
dV/dt_f   0.522/0.134n   0.500/0.182n   0.513/0.110n
R_load = 50.000
[Rising Waveform]
R_fixture= 50.000
V_fixture= 0.0
V_fixture_min= 0.0
V_fixture_max= 0.0
|time   V(typ)   V(min)   V(max)
0s        2.714uV    13.81uV    1.234uV
368ps     11.47mV    7.593mV    24.36mV
474ps     24.29mV    10.68mV    446.3mV
532ps     166.8mV    10.64mV    652.2mV
604ps     465.7mV    68.64mV    773.5mV
685ps     691.7mV    283.1mV    822.2mV
783ps     797.7mV    563.7mV    840.2mV
942ps     838mV      744.6mV    846.2mV
1.273ns   845.8mV    797.1mV    847.3mV
10ns      846.2mV    801.2mV    847.4mV
[Rising Waveform]
R_fixture= 50.000
V_fixture= 1.800
V_fixture_min= 1.750
V_fixture_max= 1.850
|time   V(typ)   V(min)   V(max)
0s        930.2mV    916.2mV    994.9mV
380ps     936.1mV    920.3mV    1.02V
406ps     936.2mV    920.9mV    1.104V
458ps     940.7mV    921.3mV    1.494V
497ps     986.9mV    922.1mV    1.662V
572ps     1.425V     942.6mV    1.793V
638ps     1.667V     1.13V      1.829V
736ps     1.769V     1.564V     1.845V
856ps     1.794V     1.715V     1.849V
10ns      1.8V       1.75V      1.85V
[Falling Waveform]
R_fixture= 50.000
V_fixture= 1.800
V_fixture_min= 1.750
V_fixture_max= 1.850
|time   V(typ)   V(min)   V(max)
0s        1.8V       1.75V      1.85V
381ps     1.8V       1.75V      1.846V
492ps     1.792V     1.751V     1.341V
550ps     1.645V     1.754V     1.14V
619ps     1.338V     1.703V     1.047V
687ps     1.109V     1.537V     1.015V
772ps     991.4mV    1.265V     1.002V
942ps     939.5mV    988.8mV    995.8mV
1.249ns   930.9mV    922.8mV    994.9mV
10ns      930.2mV    916.2mV    994.9mV
[Falling Waveform]
R_fixture= 50.000
V_fixture= 0.0
V_fixture_min= 0.0
V_fixture_max= 0.0
|time   V(typ)   V(min)   V(max)
0s        846.2mV    801.2mV    847.3mV
377ps     840.9mV    798.1mV    838.2mV
482ps     832.3mV    796.5mV    348.6mV
535ps     654.7mV    799.1mV    151.8mV
599ps     323.9mV    744mV      55.76mV
665ps     117.7mV    515.2mV    21.33mV
752ps     32.36mV    202.1mV    6.517mV
871ps     6.842mV    38.24mV    1.503mV
1.121ns   542.5uV    2.367mV    135.7uV
10ns      2.825uV    13.96uV    1.323uV
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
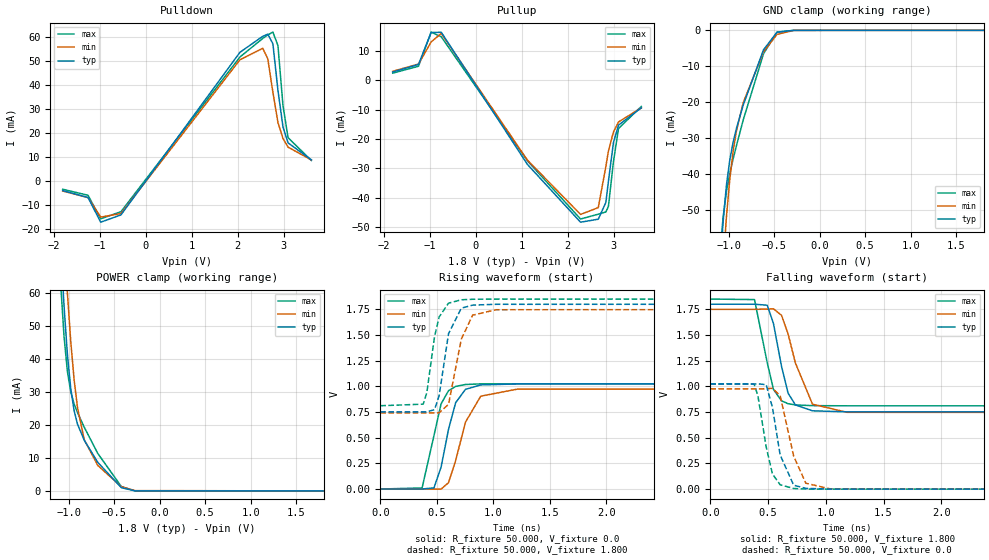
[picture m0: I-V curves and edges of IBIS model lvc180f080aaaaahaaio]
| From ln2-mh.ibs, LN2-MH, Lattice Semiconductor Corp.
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|   Model lvc180f080aaaaahaaio
[Model] lvc180f080aaaaahaaio
| Clamp models do not include dynamic input termination. Please refer to
| the lvc180axxxaaaaahaain model for input termination.
Model_type I/O
Polarity   Non-Inverting
Enable   Active-Low
Vinl =  0.630V
Vinh =  1.170V
Vmeas =  0.900V
Cref =  0.0F
Rref =  1.000M
Vref =  0.0V
C_comp   2.000pF   1.500pF   2.500pF
[Temperature Range]   25.000   0.125k   -40.000
[Voltage Range]   1.800V   1.750V   1.850V
[C Comp Corner]
C_comp   2.000pF   1.500pF   2.500pF
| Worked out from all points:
|   slope of the pulldown table from 0 to 0.27 V, typ, clamps not added: 35.6 ohm
|   slope of the pullup table from 0 to 0.27 V, typ, clamps not added: 37.1 ohm
|   GND clamp passes 1 mA (typ) near -0.49 V on its own axis
|   POWER clamp passes 1 mA (typ) near -0.42 V on its own axis
|   rising waveform, R_fixture 50.000, V_fixture 0.0: 20-80 % time 123ps typ, 152ps min, 111ps max; typ from 0 V to 1.02 V
|   rising waveform, R_fixture 50.000, V_fixture 1.800: 20-80 % time 92.4ps typ, 108ps min, 89.4ps max; typ from 0.752 V to 1.8 V
|   falling waveform, R_fixture 50.000, V_fixture 1.800: 20-80 % time 114ps typ, 149ps min, 101ps max; typ from 1.8 V to 0.752 V
|   falling waveform, R_fixture 50.000, V_fixture 0.0: 20-80 % time 97.6ps typ, 118ps min, 95.6ps max; typ from 1.02 V to 0 V
[Pulldown]
|Voltage   I(typ)   I(min)   I(max)
-1.8V     -3.995mA   -4.156mA   -3.426mA
-1.25V    -6.87mA    -6.937mA   -5.952mA
-975mV    -17.19mA   -15.06mA   -15.77mA
-535mV    -14.15mA   -13.58mA   -12.81mA
2.05V     53.77mA    50.66mA    51.81mA
2.545V    60.45mA    55.46mA    59.56mA
2.655V    61.33mA    51.01mA    61.01mA
2.765V    57.36mA    37.1mA     62.21mA
2.875V    37.94mA    24.45mA    56.6mA
2.985V    22.51mA    17.73mA    31.43mA
3.095V    15.94mA    14.16mA    18.1mA
3.6V      8.884mA    8.818mA    8.598mA
[Pullup]
|Voltage   I(typ)   I(min)   I(max)
-1.8V     2.796mA    3.021mA    2.393mA
-1.24V    5.354mA    5.497mA    4.75mA
-965mV    16.25mA    13.03mA    16.38mA
-745mV    16.31mA    15.91mA    14.77mA
1.125V    -28.66mA   -27.2mA    -27.45mA
2.28V     -48.36mA   -45.72mA   -47.28mA
2.665V    -47.34mA   -43.39mA   -45.63mA
2.83V     -41.64mA   -29.4mA    -44.87mA
2.885V    -34.47mA   -24.18mA   -43mA
2.995V    -21.23mA   -17.61mA   -27.74mA
3.105V    -15.29mA   -14.22mA   -16.45mA
3.6V      -9.406mA   -9.412mA   -8.938mA
[GND_clamp]
|Voltage   I(typ)   I(min)   I(max)
-1.8V     -570.9mA   -571.8mA   -572.9mA
-1.097V   -67.54mA   -81.64mA   -63.35mA
-1.06V    -53.45mA   -65.42mA   -52.13mA
-1.023V   -43.13mA   -51.95mA   -44.86mA
-986mV    -36.04mA   -41.41mA   -39.83mA
-949mV    -31.06mA   -33.56mA   -35.72mA
-912mV    -27.18mA   -27.83mA   -31.97mA
-838mV    -20.73mA   -20.06mA   -24.86mA
-616mV    -5.403mA   -5.958mA   -6.517mA
-468mV    -530.3uA   -1.122mA   -495.6uA
-283mV    -1.808uA   -19.61uA   -457.7nA
1.8V      0A         0A         0A
[POWER_clamp]
|Voltage   I(typ)   I(min)   I(max)
-1.789V   617.6mA    624.8mA    616.1mA
-1.086V   74.43mA    97.5mA     62.76mA
-1.049V   55.98mA    77.5mA     46.8mA
-1.012V   41.32mA    59.89mA    36.12mA
-975mV    30.91mA    45.13mA    29.96mA
-938mV    24.29mA    33.57mA    26.33mA
-901mV    20.21mA    25.16mA    23.7mA
-827mV    15.35mA    15.5mA     19.29mA
-679mV    8.657mA    7.724mA    11.36mA
-420mV    977.9uA    1.256mA    1.313mA
-272mV    22.92uA    106.7uA    14.08uA
1.8V      0A         0A         0A
[Ramp]
| variable   typ   min   max
dV/dt_r   0.614/0.123n   0.586/0.152n   0.615/0.111n
dV/dt_f   0.629/0.114n   0.605/0.149n   0.623/0.101n
R_load = 50.000
[Rising Waveform]
R_fixture= 50.000
V_fixture= 0.0
V_fixture_min= 0.0
V_fixture_max= 0.0
|time   V(typ)   V(min)   V(max)
0s        2.136uV    10.9uV     979.8nV
370ps     62.08uV    51.12uV    10.35mV
475ps     11.01mV    -344.2uV   520.2mV
538ps     212.8mV    -1.45mV    829.3mV
604ps     581.9mV    62.29mV    957.5mV
667ps     840.7mV    277mV      999.2mV
754ps     970.7mV    651.4mV    1.018V
889ps     1.014V     904.2mV    1.024V
1.21ns    1.023V     972.3mV    1.025V
10ns      1.023V     976.3mV    1.025V
[Rising Waveform]
R_fixture= 50.000
V_fixture= 1.800
V_fixture_min= 1.750
V_fixture_max= 1.850
|time   V(typ)   V(min)   V(max)
0s        751.5mV    741.2mV    811.1mV
380ps     751.4mV    741.2mV    826.6mV
412ps     751.2mV    741.2mV    939mV
480ps     773mV      740.9mV    1.483V
521ps     910.1mV    743.1mV    1.676V
604ps     1.513V     824.4mV    1.81V
717ps     1.761V     1.459V     1.843V
817ps     1.791V     1.693V     1.848V
1.024ns   1.799V     1.746V     1.85V
10ns      1.8V       1.75V      1.85V
[Falling Waveform]
R_fixture= 50.000
V_fixture= 1.800
V_fixture_min= 1.750
V_fixture_max= 1.850
|time   V(typ)   V(min)   V(max)
0s        1.8V       1.75V      1.85V
383ps     1.8V       1.75V      1.845V
493ps     1.79V      1.752V     1.232V
547ps     1.613V     1.755V     971.5mV
617ps     1.195V     1.692V     859.7mV
674ps     933.4mV    1.51V      831.5mV
737ps     820.1mV    1.228V     819.8mV
885ps     762.5mV    826.6mV    812.8mV
1.184ns   752.5mV    748mV      811.3mV
10ns      751.5mV    741.2mV    811.1mV
[Falling Waveform]
R_fixture= 50.000
V_fixture= 0.0
V_fixture_min= 0.0
V_fixture_max= 0.0
|time   V(typ)   V(min)   V(max)
0s        1.023V     976.3mV    1.025V
379ps     1.023V     976.3mV    1.024V
412ps     1.025V     976.2mV    911.8mV
484ps     1.017V     977.5mV    411.8mV
538ps     797.1mV    981.7mV    148.5mV
605ps     333.1mV    909.7mV    42.75mV
722ps     38.82mV    322.2mV    6.498mV
827ps     7.853mV    58.01mV    1.572mV
1.036ns   776.4uV    3.583mV    196.3uV
10ns      2.259uV    11.11uV    1.07uV
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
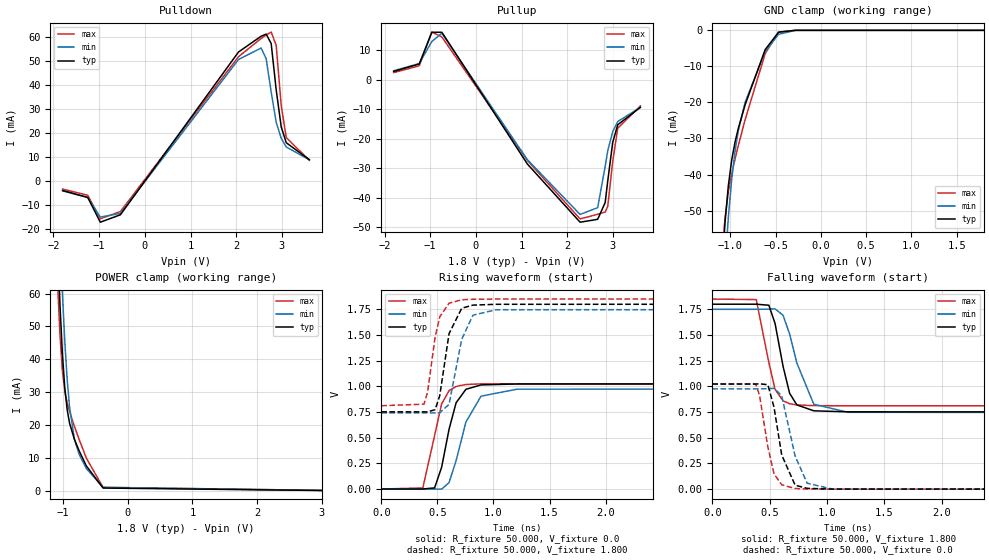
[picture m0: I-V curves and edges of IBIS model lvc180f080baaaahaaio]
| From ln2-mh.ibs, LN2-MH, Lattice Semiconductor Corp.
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|   Model lvc180f080baaaahaaio
[Model] lvc180f080baaaahaaio
| Clamp models do not include dynamic input termination. Please refer to
| the lvc180axxxbaaaahaain model for input termination.
Model_type I/O
Polarity   Non-Inverting
Enable   Active-Low
Vinl =  0.630V
Vinh =  1.170V
Vmeas =  0.900V
Cref =  0.0F
Rref =  1.000M
Vref =  0.0V
C_comp   2.000pF   1.500pF   2.500pF
[Temperature Range]   25.000   0.125k   -40.000
[Voltage Range]   1.800V   1.750V   1.850V
[C Comp Corner]
C_comp   2.000pF   1.500pF   2.500pF
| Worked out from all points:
|   slope of the pulldown table from 0 to 0.27 V, typ, clamps not added: 35.6 ohm
|   slope of the pullup table from 0 to 0.27 V, typ, clamps not added: 37.7 ohm
|   GND clamp passes 1 mA (typ) near -0.50 V on its own axis
|   POWER clamp passes 1 mA (typ) near -0.40 V on its own axis
|   rising waveform, R_fixture 50.000, V_fixture 0.0: 20-80 % time 123ps typ, 152ps min, 111ps max; typ from 0 V to 1.02 V
|   rising waveform, R_fixture 50.000, V_fixture 1.800: 20-80 % time 92.4ps typ, 108ps min, 89.4ps max; typ from 0.752 V to 1.8 V
|   falling waveform, R_fixture 50.000, V_fixture 1.800: 20-80 % time 114ps typ, 149ps min, 101ps max; typ from 1.8 V to 0.752 V
|   falling waveform, R_fixture 50.000, V_fixture 0.0: 20-80 % time 97.6ps typ, 118ps min, 95.6ps max; typ from 1.02 V to 0 V
[Pulldown]
|Voltage   I(typ)   I(min)   I(max)
-1.8V     -3.991mA   -4.152mA   -3.422mA
-1.25V    -6.863mA   -6.929mA   -5.945mA
-975mV    -17.17mA   -15.03mA   -15.74mA
-535mV    -14.08mA   -13.51mA   -12.74mA
2.05V     53.59mA    50.48mA    51.63mA
2.545V    60.15mA    55.24mA    59.21mA
2.655V    61.04mA    50.81mA    60.67mA
2.765V    57.11mA    36.97mA    61.87mA
2.875V    37.8mA     24.36mA    56.35mA
2.985V    22.42mA    17.66mA    31.3mA
3.095V    15.87mA    14.1mA     18.01mA
3.6V      8.838mA    8.777mA    8.549mA
[Pullup]
|Voltage   I(typ)   I(min)   I(max)
-1.8V     2.75mA     2.979mA    2.346mA
-1.24V    5.272mA    5.427mA    4.663mA
-965mV    16mA       12.87mA    16.07mA
-745mV    16.01mA    15.68mA    14.42mA
1.125V    -28.55mA   -27.09mA   -27.34mA
2.28V     -48.28mA   -45.65mA   -47.17mA
2.665V    -47.31mA   -43.37mA   -45.61mA
2.83V     -41.63mA   -29.38mA   -44.85mA
2.885V    -34.45mA   -24.17mA   -42.98mA
2.995V    -21.22mA   -17.6mA    -27.73mA
3.105V    -15.29mA   -14.21mA   -16.44mA
3.6V      -9.402mA   -9.407mA   -8.934mA
[GND_clamp]
|Voltage   I(typ)   I(min)   I(max)
-1.8V     -570.8mA   -571.7mA   -572.8mA
-1.097V   -67.45mA   -81.54mA   -63.25mA
-1.06V    -53.36mA   -65.33mA   -52.04mA
-1.023V   -43.04mA   -51.86mA   -44.77mA
-986mV    -35.95mA   -41.32mA   -39.74mA
-949mV    -30.97mA   -33.48mA   -35.64mA
-912mV    -27.1mA    -27.74mA   -31.88mA
-838mV    -20.66mA   -19.98mA   -24.78mA
-616mV    -5.345mA   -5.898mA   -6.456mA
-468mV    -515.9uA   -1.096mA   -482.9uA
-283mV    -1.482uA   -17.52uA   -322.5nA
1.8V      0A         0A         0A
[POWER_clamp]
|Voltage   I(typ)   I(min)   I(max)
-1.789V   617.6mA    624.8mA    616.1mA
-1.086V   74.57mA    97.6mA     62.94mA
-1.049V   56.15mA    77.62mA    47.03mA
-1.012V   41.52mA    60.02mA    36.39mA
-975mV    31.15mA    45.29mA    30.27mA
-938mV    24.56mA    33.75mA    26.65mA
-901mV    20.5mA     25.36mA    24.04mA
-827mV    15.64mA    15.72mA    19.63mA
-753mV    12.1mA     11mA       15.55mA
-642mV    7.512mA    6.704mA    9.896mA
-383mV    772.8uA    998.1uA    969uA
3.6V      -108.1uA   -110.5uA   -109.2uA
[Ramp]
| variable   typ   min   max
dV/dt_r   0.614/0.123n   0.586/0.152n   0.615/0.111n
dV/dt_f   0.629/0.114n   0.605/0.149n   0.623/0.101n
R_load = 50.000
[Rising Waveform]
R_fixture= 50.000
V_fixture= 0.0
V_fixture_min= 0.0
V_fixture_max= 0.0
|time   V(typ)   V(min)   V(max)
0s        2.136uV    10.9uV     979.8nV
370ps     62.08uV    51.12uV    10.35mV
475ps     11.01mV    -344.2uV   520.2mV
538ps     212.8mV    -1.45mV    829.3mV
604ps     581.9mV    62.29mV    957.5mV
667ps     840.7mV    277mV      999.2mV
754ps     970.7mV    651.4mV    1.018V
889ps     1.014V     904.2mV    1.024V
1.21ns    1.023V     972.3mV    1.025V
10ns      1.023V     976.3mV    1.025V
[Rising Waveform]
R_fixture= 50.000
V_fixture= 1.800
V_fixture_min= 1.750
V_fixture_max= 1.850
|time   V(typ)   V(min)   V(max)
0s        751.5mV    741.2mV    811.1mV
380ps     751.4mV    741.2mV    826.6mV
412ps     751.2mV    741.2mV    939mV
480ps     773mV      740.9mV    1.483V
521ps     910.1mV    743.1mV    1.676V
604ps     1.513V     824.4mV    1.81V
717ps     1.761V     1.459V     1.843V
817ps     1.791V     1.693V     1.848V
1.024ns   1.799V     1.746V     1.85V
10ns      1.8V       1.75V      1.85V
[Falling Waveform]
R_fixture= 50.000
V_fixture= 1.800
V_fixture_min= 1.750
V_fixture_max= 1.850
|time   V(typ)   V(min)   V(max)
0s        1.8V       1.75V      1.85V
383ps     1.8V       1.75V      1.845V
493ps     1.79V      1.752V     1.232V
547ps     1.613V     1.755V     971.5mV
617ps     1.195V     1.692V     859.7mV
674ps     933.4mV    1.51V      831.5mV
737ps     820.1mV    1.228V     819.8mV
885ps     762.5mV    826.6mV    812.8mV
1.184ns   752.5mV    748mV      811.3mV
10ns      751.5mV    741.2mV    811.1mV
[Falling Waveform]
R_fixture= 50.000
V_fixture= 0.0
V_fixture_min= 0.0
V_fixture_max= 0.0
|time   V(typ)   V(min)   V(max)
0s        1.023V     976.3mV    1.025V
379ps     1.023V     976.3mV    1.024V
412ps     1.025V     976.2mV    911.8mV
484ps     1.017V     977.5mV    411.8mV
538ps     797.1mV    981.7mV    148.5mV
605ps     333.1mV    909.7mV    42.75mV
722ps     38.82mV    322.2mV    6.498mV
827ps     7.853mV    58.01mV    1.572mV
1.036ns   776.4uV    3.583mV    196.3uV
10ns      2.259uV    11.11uV    1.07uV
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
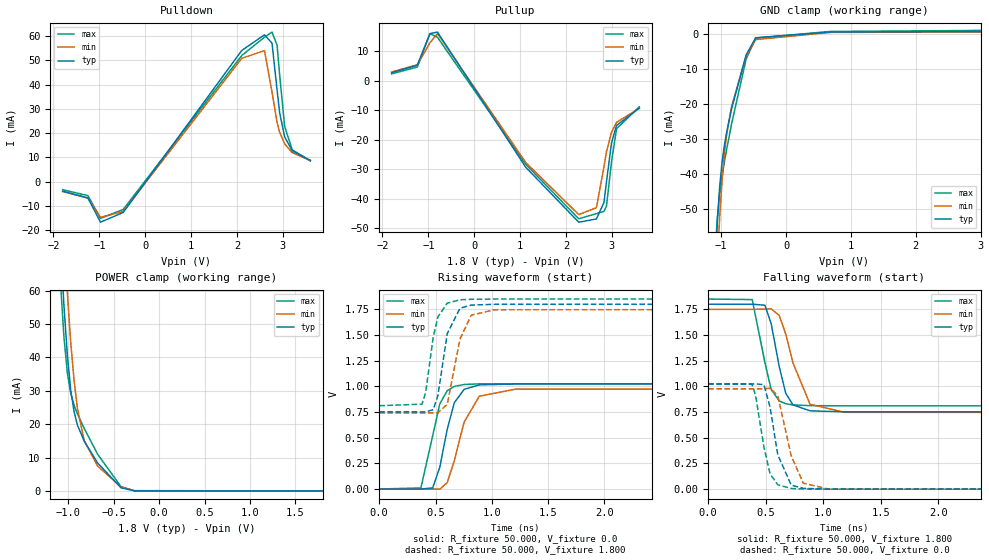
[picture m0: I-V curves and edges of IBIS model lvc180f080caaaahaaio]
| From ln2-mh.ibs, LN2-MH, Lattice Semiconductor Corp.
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|   Model lvc180f080caaaahaaio
[Model] lvc180f080caaaahaaio
| Clamp models do not include dynamic input termination. Please refer to
| the lvc180axxxcaaaahaain model for input termination.
Model_type I/O
Polarity   Non-Inverting
Enable   Active-Low
Vinl =  0.630V
Vinh =  1.170V
Vmeas =  0.900V
Cref =  0.0F
Rref =  1.000M
Vref =  0.0V
C_comp   2.000pF   1.500pF   2.500pF
[Temperature Range]   25.000   0.125k   -40.000
[Voltage Range]   1.800V   1.750V   1.850V
[C Comp Corner]
C_comp   2.000pF   1.500pF   2.500pF
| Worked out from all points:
|   slope of the pulldown table from 0 to 0.27 V, typ, clamps not added: 37 ohm
|   slope of the pullup table from 0 to 0.27 V, typ, clamps not added: 37.2 ohm
|   GND clamp passes 1 mA (typ) near -0.47 V on its own axis
|   POWER clamp passes 1 mA (typ) near -0.42 V on its own axis
|   rising waveform, R_fixture 50.000, V_fixture 0.0: 20-80 % time 123ps typ, 152ps min, 111ps max; typ from 0 V to 1.02 V
|   rising waveform, R_fixture 50.000, V_fixture 1.800: 20-80 % time 92.4ps typ, 108ps min, 89.4ps max; typ from 0.752 V to 1.8 V
|   falling waveform, R_fixture 50.000, V_fixture 1.800: 20-80 % time 114ps typ, 149ps min, 101ps max; typ from 1.8 V to 0.752 V
|   falling waveform, R_fixture 50.000, V_fixture 0.0: 20-80 % time 97.6ps typ, 118ps min, 95.6ps max; typ from 1.02 V to 0 V
[Pulldown]
|Voltage   I(typ)   I(min)   I(max)
-1.8V     -3.869mA   -4.043mA   -3.282mA
-1.25V    -6.665mA   -6.758mA   -5.713mA
-975mV    -16.67mA   -14.67mA   -15.11mA
-480mV    -12.67mA   -12.24mA   -11.42mA
2.105V    54.1mA     50.88mA    52.02mA
2.6V      60.56mA    54.04mA    59.58mA
2.765V    57.09mA    36.96mA    61.68mA
2.875V    37.8mA     24.36mA    56.27mA
2.93V     28.57mA    20.45mA    44.26mA
3.04V     18.51mA    15.62mA    22.83mA
3.205V    12.78mA    12.03mA    13.17mA
3.6V      8.849mA    8.784mA    8.552mA
[Pullup]
|Voltage   I(typ)   I(min)   I(max)
-1.8V     2.76mA     2.986mA    2.349mA
-1.24V    5.283mA    5.432mA    4.658mA
-965mV    15.98mA    12.86mA    15.93mA
-800mV    16.5mA     15.98mA    14.73mA
1.125V    -29.29mA   -27.69mA   -28.3mA
2.28V     -47.88mA   -45.31mA   -46.73mA
2.665V    -46.79mA   -42.97mA   -44.98mA
2.83V     -41.19mA   -29.12mA   -44.22mA
2.885V    -34.1mA    -23.95mA   -42.39mA
2.995V    -20.99mA   -17.43mA   -27.38mA
3.105V    -15.11mA   -14.06mA   -16.22mA
3.6V      -9.28mA    -9.301mA   -8.792mA
[GND_clamp]
|Voltage   I(typ)   I(min)   I(max)
-1.8V     -571mA     -571.9mA   -573mA
-1.097V   -67.89mA   -81.9mA    -63.82mA
-1.06V    -53.86mA   -65.72mA   -52.69mA
-1.023V   -43.6mA    -52.29mA   -45.48mA
-986mV    -36.55mA   -41.78mA   -40.47mA
-949mV    -31.59mA   -33.97mA   -36.38mA
-912mV    -27.73mA   -28.25mA   -32.63mA
-838mV    -21.28mA   -20.51mA   -25.51mA
-616mV    -5.929mA   -6.39mA    -7.151mA
-468mV    -1.006mA   -1.514mA   -1.077mA
679mV     636.6uA    525.1uA    801uA
3.6V      859.5uA    698.9uA    1.171mA
[POWER_clamp]
|Voltage   I(typ)   I(min)   I(max)
-1.789V   616.8mA    624.1mA    614.9mA
-1.086V   73.72mA    96.92mA    61.82mA
-1.049V   55.3mA     76.94mA    45.93mA
-1.012V   40.68mA    59.35mA    35.33mA
-975mV    30.32mA    44.62mA    29.25mA
-938mV    23.76mA    33.09mA    25.68mA
-901mV    19.73mA    24.71mA    23.1mA
-827mV    14.94mA    15.12mA    18.78mA
-679mV    8.384mA    7.465mA    11.01mA
-420mV    917.4uA    1.181mA    1.232mA
-272mV    19.37uA    92.48uA    11.5uA
1.8V      0A         0A         0A
[Ramp]
| variable   typ   min   max
dV/dt_r   0.614/0.123n   0.586/0.152n   0.615/0.111n
dV/dt_f   0.629/0.114n   0.605/0.149n   0.623/0.101n
R_load = 50.000
[Rising Waveform]
R_fixture= 50.000
V_fixture= 0.0
V_fixture_min= 0.0
V_fixture_max= 0.0
|time   V(typ)   V(min)   V(max)
0s        2.136uV    10.9uV     979.8nV
370ps     62.08uV    51.12uV    10.35mV
475ps     11.01mV    -344.2uV   520.2mV
538ps     212.8mV    -1.45mV    829.3mV
604ps     581.9mV    62.29mV    957.5mV
667ps     840.7mV    277mV      999.2mV
754ps     970.7mV    651.4mV    1.018V
889ps     1.014V     904.2mV    1.024V
1.21ns    1.023V     972.3mV    1.025V
10ns      1.023V     976.3mV    1.025V
[Rising Waveform]
R_fixture= 50.000
V_fixture= 1.800
V_fixture_min= 1.750
V_fixture_max= 1.850
|time   V(typ)   V(min)   V(max)
0s        751.5mV    741.2mV    811.1mV
380ps     751.4mV    741.2mV    826.6mV
412ps     751.2mV    741.2mV    939mV
480ps     773mV      740.9mV    1.483V
521ps     910.1mV    743.1mV    1.676V
604ps     1.513V     824.4mV    1.81V
717ps     1.761V     1.459V     1.843V
817ps     1.791V     1.693V     1.848V
1.024ns   1.799V     1.746V     1.85V
10ns      1.8V       1.75V      1.85V
[Falling Waveform]
R_fixture= 50.000
V_fixture= 1.800
V_fixture_min= 1.750
V_fixture_max= 1.850
|time   V(typ)   V(min)   V(max)
0s        1.8V       1.75V      1.85V
383ps     1.8V       1.75V      1.845V
493ps     1.79V      1.752V     1.232V
547ps     1.613V     1.755V     971.5mV
617ps     1.195V     1.692V     859.7mV
674ps     933.4mV    1.51V      831.5mV
737ps     820.1mV    1.228V     819.8mV
885ps     762.5mV    826.6mV    812.8mV
1.184ns   752.5mV    748mV      811.3mV
10ns      751.5mV    741.2mV    811.1mV
[Falling Waveform]
R_fixture= 50.000
V_fixture= 0.0
V_fixture_min= 0.0
V_fixture_max= 0.0
|time   V(typ)   V(min)   V(max)
0s        1.023V     976.3mV    1.025V
379ps     1.023V     976.3mV    1.024V
412ps     1.025V     976.2mV    911.8mV
484ps     1.017V     977.5mV    411.8mV
538ps     797.1mV    981.7mV    148.5mV
605ps     333.1mV    909.7mV    42.75mV
722ps     38.82mV    322.2mV    6.498mV
827ps     7.853mV    58.01mV    1.572mV
1.036ns   776.4uV    3.583mV    196.3uV
10ns      2.259uV    11.11uV    1.07uV
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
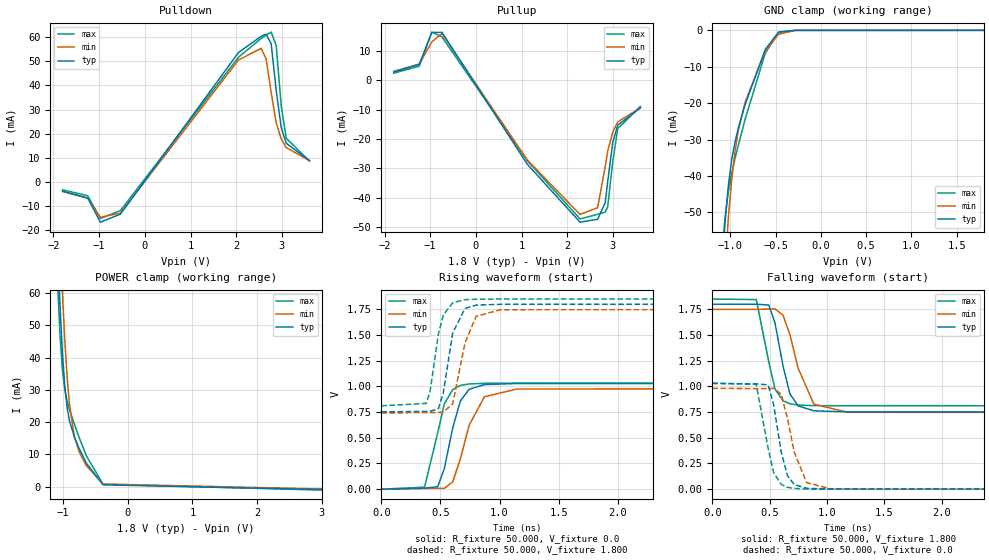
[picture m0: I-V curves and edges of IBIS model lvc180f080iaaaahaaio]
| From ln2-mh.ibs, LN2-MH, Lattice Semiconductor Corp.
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|   Model lvc180f080iaaaahaaio
[Model] lvc180f080iaaaahaaio
| Clamp models do not include dynamic input termination. Please refer to
| the lvc180axxxiaaaahaain model for input termination.
Model_type I/O
Polarity   Non-Inverting
Enable   Active-Low
Vinl =  0.630V
Vinh =  1.170V
Vmeas =  0.900V
Cref =  0.0F
Rref =  1.000M
Vref =  0.0V
C_comp   2.000pF   1.500pF   2.500pF
[Temperature Range]   25.000   0.125k   -40.000
[Voltage Range]   1.800V   1.750V   1.850V
[C Comp Corner]
C_comp   2.000pF   1.500pF   2.500pF
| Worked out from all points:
|   slope of the pulldown table from 0 to 0.27 V, typ, clamps not added: 36 ohm
|   slope of the pullup table from 0 to 0.27 V, typ, clamps not added: 37.2 ohm
|   GND clamp passes 1 mA (typ) near -0.50 V on its own axis
|   POWER clamp passes 1 mA (typ) near -0.41 V on its own axis
|   rising waveform, R_fixture 50.000, V_fixture 0.0: 20-80 % time 122ps typ, 151ps min, 110ps max; typ from 0 V to 1.03 V
|   rising waveform, R_fixture 50.000, V_fixture 1.800: 20-80 % time 91.8ps typ, 107ps min, 88.6ps max; typ from 0.752 V to 1.8 V
|   falling waveform, R_fixture 50.000, V_fixture 1.800: 20-80 % time 114ps typ, 149ps min, 101ps max; typ from 1.8 V to 0.752 V
|   falling waveform, R_fixture 50.000, V_fixture 0.0: 20-80 % time 97.9ps typ, 118ps min, 96.1ps max; typ from 1.03 V to 0 V
[Pulldown]
|Voltage   I(typ)   I(min)   I(max)
-1.8V     -3.942mA   -4.106mA   -3.364mA
-1.25V    -6.76mA    -6.838mA   -5.82mA
-975mV    -16.81mA   -14.78mA   -15.27mA
-535mV    -13.49mA   -13.03mA   -12mA
2.05V     53.69mA    50.59mA    51.73mA
2.545V    60.4mA     55.42mA    59.5mA
2.655V    61.28mA    50.97mA    60.96mA
2.765V    57.32mA    37.08mA    62.16mA
2.875V    37.92mA    24.44mA    56.57mA
2.985V    22.5mA     17.72mA    31.41mA
3.095V    15.93mA    14.15mA    18.09mA
3.6V      8.878mA    8.811mA    8.591mA
[Pullup]
|Voltage   I(typ)   I(min)   I(max)
-1.8V     2.796mA    3.021mA    2.393mA
-1.24V    5.354mA    5.497mA    4.75mA
-965mV    16.25mA    13.03mA    16.38mA
-745mV    16.31mA    15.91mA    14.77mA
1.125V    -28.64mA   -27.18mA   -27.43mA
2.28V     -48.36mA   -45.73mA   -47.25mA
2.665V    -47.37mA   -43.43mA   -45.67mA
2.83V     -41.71mA   -29.44mA   -44.92mA
2.885V    -34.54mA   -24.22mA   -43.07mA
2.995V    -21.26mA   -17.63mA   -27.82mA
3.105V    -15.31mA   -14.22mA   -16.48mA
3.6V      -9.408mA   -9.413mA   -8.941mA
[GND_clamp]
|Voltage   I(typ)   I(min)   I(max)
-1.8V     -569.8mA   -570.8mA   -571.6mA
-1.097V   -66.86mA   -81.02mA   -62.54mA
-1.06V    -52.83mA   -64.84mA   -51.42mA
-1.023V   -42.57mA   -51.42mA   -44.23mA
-986mV    -35.54mA   -40.92mA   -39.25mA
-949mV    -30.61mA   -33.13mA   -35.19mA
-912mV    -26.78mA   -27.43mA   -31.48mA
-838mV    -20.4mA    -19.75mA   -24.45mA
-616mV    -5.27mA    -5.819mA   -6.352mA
-468mV    -506.6uA   -1.081mA   -470.6uA
-283mV    -1.427uA   -17.24uA   -284.7nA
1.8V      0A         0A         0A
[POWER_clamp]
|Voltage   I(typ)   I(min)   I(max)
-1.789V   617.6mA    624.8mA    616.1mA
-1.086V   74.45mA    97.52mA    62.79mA
-1.049V   56mA       77.52mA    46.83mA
-1.012V   41.34mA    59.91mA    36.16mA
-975mV    30.94mA    45.16mA    30mA
-938mV    24.33mA    33.6mA     26.37mA
-901mV    20.25mA    25.2mA     23.75mA
-827mV    15.39mA    15.54mA    19.34mA
-753mV    11.85mA    10.81mA    15.26mA
-642mV    7.266mA    6.521mA    9.605mA
-383mV    595.8uA    860.9uA    753.9uA
3.6V      -1.113mA   -985.8uA   -1.346mA
[Ramp]
| variable   typ   min   max
dV/dt_r   0.617/0.122n   0.589/0.151n   0.619/0.110n
dV/dt_f   0.629/0.114n   0.605/0.150n   0.623/0.101n
R_load = 50.000
[Rising Waveform]
R_fixture= 50.000
V_fixture= 0.0
V_fixture_min= 0.0
V_fixture_max= 0.0
|time   V(typ)   V(min)   V(max)
0s        2.136uV    10.9uV     979.8nV
366ps     9.676mV    6.587mV    19.56mV
477ps     24.1mV     8.74mV     548.7mV
533ps     199.6mV    8.165mV    828.5mV
604ps     595.6mV    71.52mV    969.7mV
669ps     858.8mV    296.1mV    1.01V
743ps     971.8mV    622.5mV    1.024V
872ps     1.018V     899mV      1.03V
1.148ns   1.028V     974.8mV    1.032V
10ns      1.028V     980.9mV    1.032V
[Rising Waveform]
R_fixture= 50.000
V_fixture= 1.800
V_fixture_min= 1.750
V_fixture_max= 1.850
|time   V(typ)   V(min)   V(max)
0s        751.5mV    741.2mV    811.1mV
380ps     757.4mV    745.5mV    834.8mV
412ps     757.5mV    746.1mV    948.1mV
483ps     784.5mV    746.4mV    1.51V
524ps     936.2mV    749.1mV    1.693V
604ps     1.521V     830.9mV    1.815V
708ps     1.759V     1.423V     1.844V
802ps     1.791V     1.682V     1.848V
1.008ns   1.799V     1.746V     1.85V
10ns      1.8V       1.75V      1.85V
[Falling Waveform]
R_fixture= 50.000
V_fixture= 1.800
V_fixture_min= 1.750
V_fixture_max= 1.850
|time   V(typ)   V(min)   V(max)
0s        1.8V       1.75V      1.85V
383ps     1.8V       1.75V      1.845V
492ps     1.792V     1.752V     1.238V
546ps     1.618V     1.755V     974.3mV
617ps     1.195V     1.692V     859.7mV
676ps     927.4mV    1.502V     830.9mV
748ps     810mV      1.177V     818.6mV
885ps     762.5mV    826.6mV    812.8mV
1.183ns   752.5mV    748mV      811.3mV
10ns      751.5mV    741.2mV    811.1mV
[Falling Waveform]
R_fixture= 50.000
V_fixture= 0.0
V_fixture_min= 0.0
V_fixture_max= 0.0
|time   V(typ)   V(min)   V(max)
0s        1.028V     980.9mV    1.032V
382ps     1.025V     978.7mV    1.021V
486ps     1.015V     978.4mV    398.8mV
534ps     823.4mV    982mV      160.6mV
600ps     362.4mV    923.8mV    46.7mV
655ps     131.3mV    688.8mV    18.35mV
714ps     44.38mV    359.6mV    7.314mV
822ps     8.676mV    63.14mV    1.673mV
1.029ns   856.8uV    3.855mV    208uV
10ns      2.259uV    11.11uV    1.07uV
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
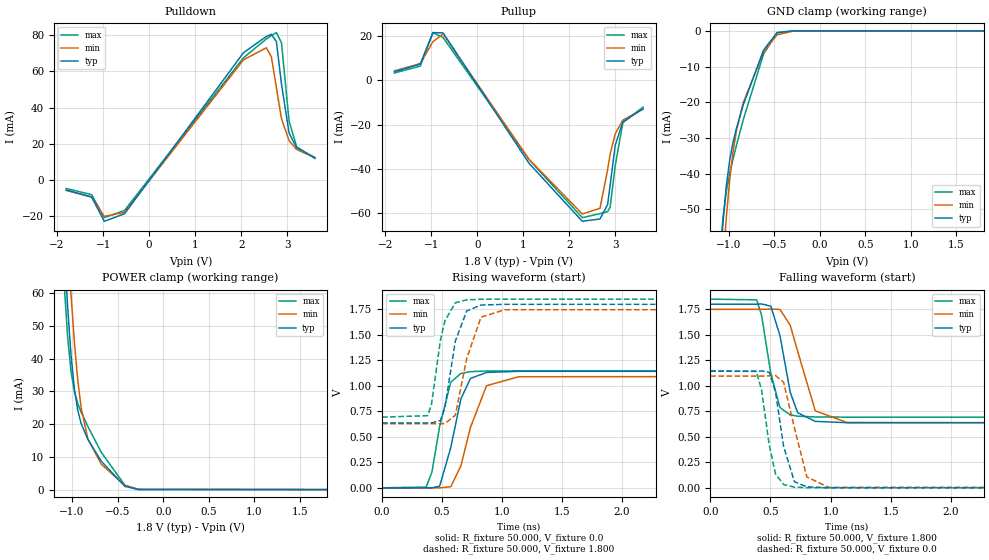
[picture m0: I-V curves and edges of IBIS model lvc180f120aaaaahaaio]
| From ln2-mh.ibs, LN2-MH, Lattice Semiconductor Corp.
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|   Model lvc180f120aaaaahaaio
[Model] lvc180f120aaaaahaaio
| Clamp models do not include dynamic input termination. Please refer to
| the lvc180axxxaaaaahaain model for input termination.
Model_type I/O
Polarity   Non-Inverting
Enable   Active-Low
Vinl =  0.630V
Vinh =  1.170V
Vmeas =  0.900V
Cref =  0.0F
Rref =  1.000M
Vref =  0.0V
C_comp   2.000pF   1.500pF   2.500pF
[Temperature Range]   25.000   0.125k   -40.000
[Voltage Range]   1.800V   1.750V   1.850V
[C Comp Corner]
C_comp   2.000pF   1.500pF   2.500pF
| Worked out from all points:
|   slope of the pulldown table from 0 to 0.27 V, typ, clamps not added: 27.2 ohm
|   slope of the pullup table from 0 to 0.27 V, typ, clamps not added: 28.4 ohm
|   GND clamp passes 1 mA (typ) near -0.49 V on its own axis
|   POWER clamp passes 1 mA (typ) near -0.42 V on its own axis
|   rising waveform, R_fixture 50.000, V_fixture 0.0: 20-80 % time 123ps typ, 150ps min, 107ps max; typ from 0 V to 1.14 V
|   rising waveform, R_fixture 50.000, V_fixture 1.800: 20-80 % time 104ps typ, 119ps min, 94.4ps max; typ from 0.637 V to 1.8 V
|   falling waveform, R_fixture 50.000, V_fixture 1.800: 20-80 % time 113ps typ, 147ps min, 96.9ps max; typ from 1.8 V to 0.637 V
|   falling waveform, R_fixture 50.000, V_fixture 0.0: 20-80 % time 92.3ps typ, 113ps min, 87.2ps max; typ from 1.14 V to 0 V
[Pulldown]
|Voltage   I(typ)   I(min)   I(max)
-1.8V     -5.444mA   -5.69mA    -4.62mA
-1.25V    -9.268mA   -9.362mA   -7.974mA
-975mV    -22.72mA   -19.99mA   -20.69mA
-535mV    -18.56mA   -17.82mA   -16.75mA
2.05V     70.36mA    66.44mA    67.56mA
2.545V    79.31mA    73.08mA    77.91mA
2.655V    80.56mA    68.14mA    79.84mA
2.765V    76.46mA    51.05mA    81.48mA
2.875V    53.11mA    33.98mA    75.82mA
3.04V     25.98mA    21.83mA    32.57mA
3.205V    17.87mA    16.88mA    18.41mA
3.6V      12.49mA    12.49mA    11.98mA
[Pullup]
|Voltage   I(typ)   I(min)   I(max)
-1.8V     3.926mA    4.274mA    3.323mA
-1.24V    7.345mA    7.543mA    6.433mA
-965mV    21.59mA    17.47mA    21.54mA
-745mV    21.44mA    20.98mA    19.34mA
1.125V    -37.6mA    -35.79mA   -35.89mA
2.28V     -63.77mA   -60.45mA   -62.13mA
2.665V    -62.7mA    -57.88mA   -60.29mA
2.83V     -56.13mA   -40.31mA   -59.39mA
2.885V    -47.33mA   -33.31mA   -57.3mA
2.995V    -29.37mA   -24.18mA   -38.6mA
3.16V     -18.8mA    -18.02mA   -19.16mA
3.6V      -12.88mA   -12.98mA   -12.14mA
[GND_clamp]
|Voltage   I(typ)   I(min)   I(max)
-1.8V     -570.9mA   -571.8mA   -572.9mA
-1.097V   -67.54mA   -81.64mA   -63.35mA
-1.06V    -53.45mA   -65.42mA   -52.13mA
-1.023V   -43.13mA   -51.95mA   -44.86mA
-986mV    -36.04mA   -41.41mA   -39.83mA
-949mV    -31.06mA   -33.56mA   -35.72mA
-912mV    -27.18mA   -27.83mA   -31.97mA
-838mV    -20.73mA   -20.06mA   -24.86mA
-616mV    -5.403mA   -5.958mA   -6.517mA
-468mV    -530.3uA   -1.122mA   -495.6uA
-283mV    -1.808uA   -19.61uA   -457.7nA
1.8V      0A         0A         0A
[POWER_clamp]
|Voltage   I(typ)   I(min)   I(max)
-1.789V   617.6mA    624.8mA    616.1mA
-1.086V   74.43mA    97.5mA     62.76mA
-1.049V   55.98mA    77.5mA     46.8mA
-1.012V   41.32mA    59.89mA    36.12mA
-975mV    30.91mA    45.13mA    29.96mA
-938mV    24.29mA    33.57mA    26.33mA
-901mV    20.21mA    25.16mA    23.7mA
-827mV    15.35mA    15.5mA     19.29mA
-679mV    8.657mA    7.724mA    11.36mA
-420mV    977.9uA    1.256mA    1.313mA
-272mV    22.92uA    106.7uA    14.08uA
1.8V      0A         0A         0A
[Ramp]
| variable   typ   min   max
dV/dt_r   0.686/0.123n   0.657/0.150n   0.688/0.107n
dV/dt_f   0.698/0.113n   0.673/0.147n   0.694/96.970p
R_load = 50.000
[Rising Waveform]
R_fixture= 50.000
V_fixture= 0.0
V_fixture_min= 0.0
V_fixture_max= 0.0
|time   V(typ)   V(min)   V(max)
0s        1.76uV     9.003uV    814.4nV
367ps     66.61uV    40.9uV     6.543mV
416ps     -686.4uV   73.35uV    153.9mV
480ps     15.85mV    -478.7uV   602.5mV
573ps     395mV      10.53mV    1.036V
657ps     871.1mV    213.7mV    1.121V
737ps     1.072V     591.8mV    1.139V
871ps     1.131V     1.001V     1.145V
1.14ns    1.142V     1.089V     1.146V
10ns      1.143V     1.096V     1.147V
[Rising Waveform]
R_fixture= 50.000
V_fixture= 1.800
V_fixture_min= 1.750
V_fixture_max= 1.850
|time   V(typ)   V(min)   V(max)
0s        636.5mV    628.2mV    692.9mV
380ps     636.5mV    628.2mV    707.4mV
412ps     636.1mV    628.2mV    817.1mV
486ps     659.1mV    627.8mV    1.443V
524ps     787.9mV    629.8mV    1.637V
611ps     1.438V     711.6mV    1.814V
706ps     1.734V     1.269V     1.843V
825ps     1.792V     1.673V     1.849V
1.023ns   1.799V     1.746V     1.85V
10ns      1.8V       1.75V      1.85V
[Falling Waveform]
R_fixture= 50.000
V_fixture= 1.800
V_fixture_min= 1.750
V_fixture_max= 1.850
|time   V(typ)   V(min)   V(max)
0s        1.8V       1.75V      1.85V
385ps     1.8V       1.75V      1.843V
426ps     1.803V     1.75V      1.692V
503ps     1.781V     1.752V     1.121V
579ps     1.492V     1.749V     786.6mV
664ps     937mV      1.594V     715.2mV
726ps     736.6mV    1.338V     702.6mV
872ps     651.8mV    755.5mV    695.2mV
1.136ns   638.8mV    640.3mV    693.2mV
10ns      636.5mV    628.2mV    692.9mV
[Falling Waveform]
R_fixture= 50.000
V_fixture= 0.0
V_fixture_min= 0.0
V_fixture_max= 0.0
|time   V(typ)   V(min)   V(max)
0s        1.143V     1.096V     1.146V
383ps     1.143V     1.096V     1.141V
426ps     1.146V     1.096V     960.2mV
490ps     1.132V     1.097V     417.8mV
542ps     938.4mV    1.101V     136.3mV
609ps     407.1mV    1.035V     33.02mV
699ps     60.27mV    588.7mV    7.043mV
802ps     9.855mV    107.4mV    1.686mV
981ps     1.267mV    6.154mV    291.5uV
10ns      1.883uV    9.238uV    902.5nV
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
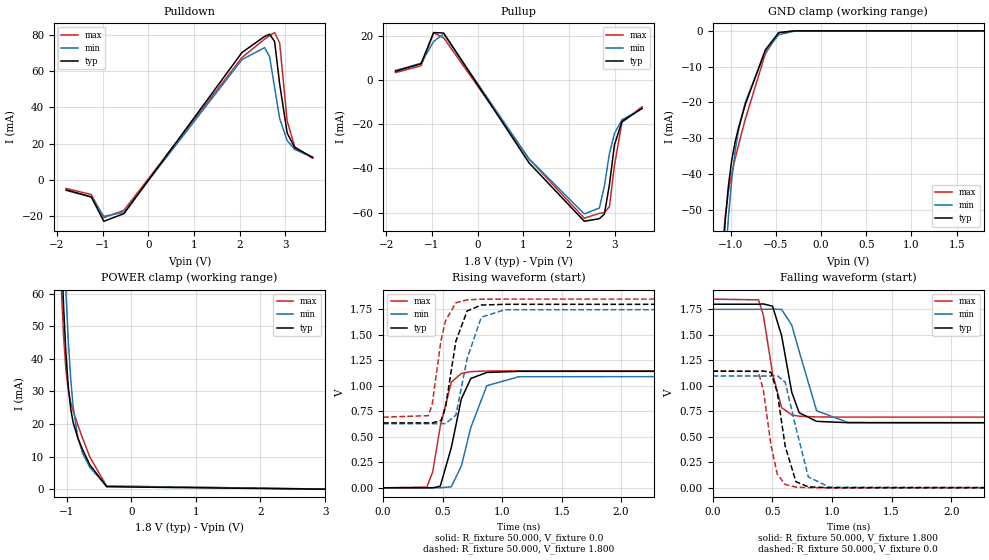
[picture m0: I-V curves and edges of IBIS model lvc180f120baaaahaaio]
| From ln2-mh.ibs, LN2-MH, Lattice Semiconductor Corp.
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|   Model lvc180f120baaaahaaio
[Model] lvc180f120baaaahaaio
| Clamp models do not include dynamic input termination. Please refer to
| the lvc180axxxbaaaahaain model for input termination.
Model_type I/O
Polarity   Non-Inverting
Enable   Active-Low
Vinl =  0.630V
Vinh =  1.170V
Vmeas =  0.900V
Cref =  0.0F
Rref =  1.000M
Vref =  0.0V
C_comp   2.000pF   1.500pF   2.500pF
[Temperature Range]   25.000   0.125k   -40.000
[Voltage Range]   1.800V   1.750V   1.850V
[C Comp Corner]
C_comp   2.000pF   1.500pF   2.500pF
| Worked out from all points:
|   slope of the pulldown table from 0 to 0.27 V, typ, clamps not added: 27.2 ohm
|   slope of the pullup table from 0 to 0.27 V, typ, clamps not added: 28.7 ohm
|   GND clamp passes 1 mA (typ) near -0.50 V on its own axis
|   POWER clamp passes 1 mA (typ) near -0.40 V on its own axis
|   rising waveform, R_fixture 50.000, V_fixture 0.0: 20-80 % time 123ps typ, 150ps min, 107ps max; typ from 0 V to 1.14 V
|   rising waveform, R_fixture 50.000, V_fixture 1.800: 20-80 % time 104ps typ, 119ps min, 94.4ps max; typ from 0.637 V to 1.8 V
|   falling waveform, R_fixture 50.000, V_fixture 1.800: 20-80 % time 113ps typ, 147ps min, 96.9ps max; typ from 1.8 V to 0.637 V
|   falling waveform, R_fixture 50.000, V_fixture 0.0: 20-80 % time 92.3ps typ, 113ps min, 87.2ps max; typ from 1.14 V to 0 V
[Pulldown]
|Voltage   I(typ)   I(min)   I(max)
-1.8V     -5.44mA    -5.685mA   -4.615mA
-1.25V    -9.261mA   -9.353mA   -7.967mA
-975mV    -22.7mA    -19.97mA   -20.66mA
-535mV    -18.49mA   -17.75mA   -16.67mA
2.05V     70.18mA    66.27mA    67.38mA
2.545V    79.01mA    72.86mA    77.56mA
2.655V    80.27mA    67.95mA    79.5mA
2.765V    76.22mA    50.91mA    81.15mA
2.875V    52.96mA    33.89mA    75.56mA
3.04V     25.9mA     21.76mA    32.47mA
3.205V    17.81mA    16.83mA    18.34mA
3.6V      12.44mA    12.45mA    11.93mA
[Pullup]
|Voltage   I(typ)   I(min)   I(max)
-1.8V     3.88mA     4.232mA    3.276mA
-1.24V    7.264mA    7.474mA    6.347mA
-965mV    21.35mA    17.32mA    21.22mA
-745mV    21.14mA    20.75mA    18.99mA
1.125V    -37.49mA   -35.68mA   -35.79mA
2.335V    -63.87mA   -60.54mA   -62.49mA
2.665V    -62.67mA   -57.86mA   -60.26mA
2.775V    -60.62mA   -47.94mA   -59.89mA
2.885V    -47.32mA   -33.3mA    -57.28mA
2.995V    -29.36mA   -24.17mA   -38.59mA
3.16V     -18.79mA   -18.01mA   -19.16mA
3.6V      -12.88mA   -12.97mA   -12.14mA
[GND_clamp]
|Voltage   I(typ)   I(min)   I(max)
-1.8V     -570.8mA   -571.7mA   -572.8mA
-1.097V   -67.45mA   -81.54mA   -63.25mA
-1.06V    -53.36mA   -65.33mA   -52.04mA
-1.023V   -43.04mA   -51.86mA   -44.77mA
-986mV    -35.95mA   -41.32mA   -39.74mA
-949mV    -30.97mA   -33.48mA   -35.64mA
-912mV    -27.1mA    -27.74mA   -31.88mA
-838mV    -20.66mA   -19.98mA   -24.78mA
-616mV    -5.345mA   -5.898mA   -6.456mA
-468mV    -515.9uA   -1.096mA   -482.9uA
-283mV    -1.482uA   -17.52uA   -322.5nA
1.8V      0A         0A         0A
[POWER_clamp]
|Voltage   I(typ)   I(min)   I(max)
-1.789V   617.6mA    624.8mA    616.1mA
-1.086V   74.57mA    97.6mA     62.94mA
-1.049V   56.15mA    77.62mA    47.03mA
-1.012V   41.52mA    60.02mA    36.39mA
-975mV    31.15mA    45.29mA    30.27mA
-938mV    24.56mA    33.75mA    26.65mA
-901mV    20.5mA     25.36mA    24.04mA
-827mV    15.64mA    15.73mA    19.63mA
-753mV    12.1mA     11mA       15.55mA
-642mV    7.512mA    6.704mA    9.896mA
-383mV    772.8uA    998.1uA    969uA
3.6V      -108.1uA   -110.5uA   -109.2uA
[Ramp]
| variable   typ   min   max
dV/dt_r   0.686/0.123n   0.657/0.150n   0.688/0.107n
dV/dt_f   0.698/0.113n   0.673/0.147n   0.694/96.970p
R_load = 50.000
[Rising Waveform]
R_fixture= 50.000
V_fixture= 0.0
V_fixture_min= 0.0
V_fixture_max= 0.0
|time   V(typ)   V(min)   V(max)
0s        1.76uV     9.003uV    814.4nV
367ps     66.61uV    40.9uV     6.543mV
416ps     -686.4uV   73.35uV    153.9mV
480ps     15.85mV    -478.7uV   602.5mV
573ps     395mV      10.53mV    1.036V
657ps     871.1mV    213.7mV    1.121V
737ps     1.072V     591.8mV    1.139V
871ps     1.131V     1.001V     1.145V
1.14ns    1.142V     1.089V     1.146V
10ns      1.143V     1.096V     1.147V
[Rising Waveform]
R_fixture= 50.000
V_fixture= 1.800
V_fixture_min= 1.750
V_fixture_max= 1.850
|time   V(typ)   V(min)   V(max)
0s        636.5mV    628.2mV    692.9mV
380ps     636.5mV    628.2mV    707.4mV
412ps     636.1mV    628.2mV    817.1mV
486ps     659.1mV    627.8mV    1.443V
524ps     787.9mV    629.8mV    1.637V
611ps     1.438V     711.6mV    1.814V
706ps     1.734V     1.269V     1.843V
825ps     1.792V     1.673V     1.849V
1.023ns   1.799V     1.746V     1.85V
10ns      1.8V       1.75V      1.85V
[Falling Waveform]
R_fixture= 50.000
V_fixture= 1.800
V_fixture_min= 1.750
V_fixture_max= 1.850
|time   V(typ)   V(min)   V(max)
0s        1.8V       1.75V      1.85V
385ps     1.8V       1.75V      1.843V
426ps     1.803V     1.75V      1.692V
503ps     1.781V     1.752V     1.121V
579ps     1.492V     1.749V     786.6mV
664ps     937mV      1.594V     715.2mV
726ps     736.6mV    1.338V     702.6mV
872ps     651.8mV    755.5mV    695.2mV
1.136ns   638.8mV    640.3mV    693.2mV
10ns      636.5mV    628.2mV    692.9mV
[Falling Waveform]
R_fixture= 50.000
V_fixture= 0.0
V_fixture_min= 0.0
V_fixture_max= 0.0
|time   V(typ)   V(min)   V(max)
0s        1.143V     1.096V     1.146V
383ps     1.143V     1.096V     1.141V
426ps     1.146V     1.096V     960.2mV
490ps     1.132V     1.097V     417.8mV
542ps     938.4mV    1.101V     136.3mV
609ps     407.1mV    1.035V     33.02mV
699ps     60.27mV    588.7mV    7.043mV
802ps     9.855mV    107.4mV    1.686mV
981ps     1.267mV    6.154mV    291.5uV
10ns      1.883uV    9.238uV    902.5nV
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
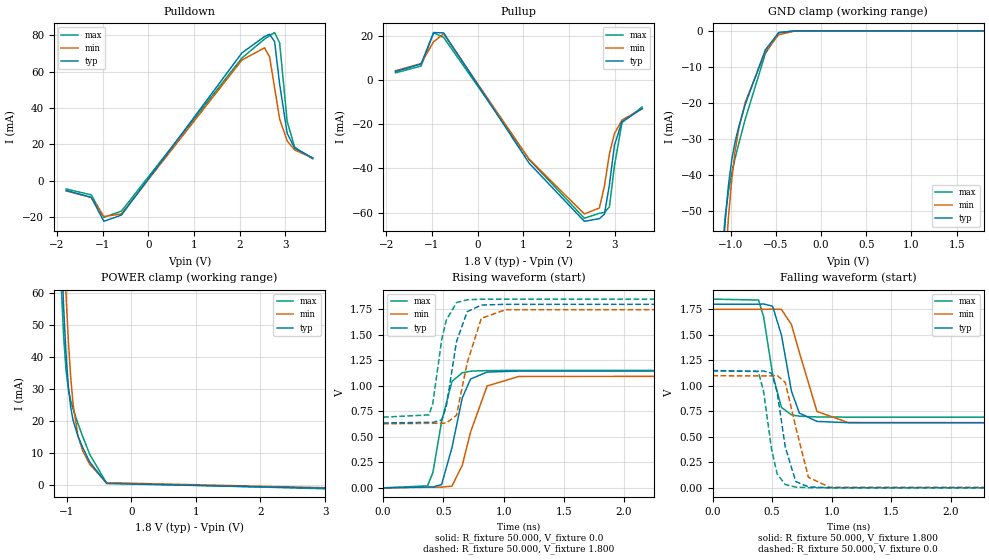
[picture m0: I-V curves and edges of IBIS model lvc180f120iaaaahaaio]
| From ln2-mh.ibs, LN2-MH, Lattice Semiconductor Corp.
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|   Model lvc180f120iaaaahaaio
[Model] lvc180f120iaaaahaaio
| Clamp models do not include dynamic input termination. Please refer to
| the lvc180axxxiaaaahaain model for input termination.
Model_type I/O
Polarity   Non-Inverting
Enable   Active-Low
Vinl =  0.630V
Vinh =  1.170V
Vmeas =  0.900V
Cref =  0.0F
Rref =  1.000M
Vref =  0.0V
C_comp   2.000pF   1.500pF   2.500pF
[Temperature Range]   25.000   0.125k   -40.000
[Voltage Range]   1.800V   1.750V   1.850V
[C Comp Corner]
C_comp   2.000pF   1.500pF   2.500pF
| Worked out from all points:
|   slope of the pulldown table from 0 to 0.27 V, typ, clamps not added: 27.5 ohm
|   slope of the pullup table from 0 to 0.27 V, typ, clamps not added: 28.4 ohm
|   GND clamp passes 1 mA (typ) near -0.50 V on its own axis
|   POWER clamp passes 1 mA (typ) near -0.41 V on its own axis
|   rising waveform, R_fixture 50.000, V_fixture 0.0: 20-80 % time 122ps typ, 149ps min, 106ps max; typ from 0 V to 1.15 V
|   rising waveform, R_fixture 50.000, V_fixture 1.800: 20-80 % time 103ps typ, 119ps min, 93.6ps max; typ from 0.637 V to 1.8 V
|   falling waveform, R_fixture 50.000, V_fixture 1.800: 20-80 % time 113ps typ, 147ps min, 96.9ps max; typ from 1.8 V to 0.637 V
|   falling waveform, R_fixture 50.000, V_fixture 0.0: 20-80 % time 92.6ps typ, 113ps min, 87.5ps max; typ from 1.15 V to 0 V
[Pulldown]
|Voltage   I(typ)   I(min)   I(max)
-1.8V     -5.391mA   -5.64mA    -4.557mA
-1.25V    -9.158mA   -9.262mA   -7.842mA
-975mV    -22.35mA   -19.72mA   -20.19mA
-590mV    -18.95mA   -18.33mA   -16.75mA
2.05V     70.28mA    66.37mA    67.48mA
2.545V    79.26mA    73.04mA    77.85mA
2.655V    80.52mA    68.1mA     79.79mA
2.765V    76.43mA    51.02mA    81.44mA
2.875V    53.09mA    33.96mA    75.79mA
3.04V     25.97mA    21.82mA    32.56mA
3.205V    17.86mA    16.87mA    18.4mA
3.6V      12.48mA    12.48mA    11.97mA
[Pullup]
|Voltage   I(typ)   I(min)   I(max)
-1.8V     3.926mA    4.274mA    3.323mA
-1.24V    7.346mA    7.544mA    6.434mA
-965mV    21.59mA    17.48mA    21.54mA
-745mV    21.44mA    20.98mA    19.34mA
1.125V    -37.57mA   -35.77mA   -35.87mA
2.335V    -63.95mA   -60.61mA   -62.57mA
2.665V    -62.74mA   -57.93mA   -60.33mA
2.775V    -60.7mA    -48.03mA   -59.96mA
2.885V    -47.43mA   -33.35mA   -57.38mA
2.995V    -29.42mA   -24.2mA    -38.72mA
3.16V     -18.81mA   -18.03mA   -19.19mA
3.6V      -12.88mA   -12.98mA   -12.15mA
[GND_clamp]
|Voltage   I(typ)   I(min)   I(max)
-1.8V     -569.8mA   -570.8mA   -571.6mA
-1.097V   -66.86mA   -81.02mA   -62.54mA
-1.06V    -52.83mA   -64.84mA   -51.42mA
-1.023V   -42.57mA   -51.42mA   -44.23mA
-986mV    -35.54mA   -40.92mA   -39.25mA
-949mV    -30.61mA   -33.13mA   -35.19mA
-912mV    -26.78mA   -27.43mA   -31.48mA
-838mV    -20.4mA    -19.75mA   -24.45mA
-616mV    -5.27mA    -5.819mA   -6.352mA
-468mV    -506.5uA   -1.081mA   -470.6uA
-283mV    -1.427uA   -17.24uA   -284.7nA
1.8V      0A         0A         0A
[POWER_clamp]
|Voltage   I(typ)   I(min)   I(max)
-1.789V   617.6mA    624.8mA    616.1mA
-1.086V   74.45mA    97.52mA    62.79mA
-1.049V   56mA       77.52mA    46.83mA
-1.012V   41.34mA    59.91mA    36.16mA
-975mV    30.94mA    45.16mA    30mA
-938mV    24.33mA    33.6mA     26.37mA
-901mV    20.25mA    25.2mA     23.75mA
-827mV    15.39mA    15.54mA    19.34mA
-753mV    11.85mA    10.81mA    15.26mA
-642mV    7.266mA    6.521mA    9.605mA
-383mV    595.8uA    860.9uA    753.9uA
3.6V      -1.113mA   -985.8uA   -1.346mA
[Ramp]
| variable   typ   min   max
dV/dt_r   0.688/0.122n   0.659/0.149n   0.691/0.106n
dV/dt_f   0.698/0.113n   0.673/0.147n   0.694/96.897p
R_load = 50.000
[Rising Waveform]
R_fixture= 50.000
V_fixture= 0.0
V_fixture_min= 0.0
V_fixture_max= 0.0
|time   V(typ)   V(min)   V(max)
0s        1.76uV     9.003uV    814.4nV
368ps     8.45mV     5.971mV    19.39mV
413ps     8.323mV    7.161mV    149.7mV
485ps     32.14mV    7.28mV     651.3mV
571ps     393.4mV    16.97mV    1.043V
657ps     882.6mV    222.3mV    1.128V
726ps     1.067V     548.7mV    1.144V
863ps     1.135V     998.8mV    1.15V
1.126ns   1.145V     1.092V     1.151V
10ns      1.146V     1.099V     1.151V
[Rising Waveform]
R_fixture= 50.000
V_fixture= 1.800
V_fixture_min= 1.750
V_fixture_max= 1.850
|time   V(typ)   V(min)   V(max)
0s        636.5mV    628.2mV    692.9mV
380ps     642.2mV    632.4mV    715.2mV
412ps     642.1mV    632.9mV    825.7mV
486ps     665.6mV    633mV      1.452V
524ps     795.3mV    635.2mV    1.644V
609ps     1.434V     711.7mV    1.816V
698ps     1.727V     1.228V     1.844V
815ps     1.792V     1.662V     1.849V
1.015ns   1.799V     1.746V     1.85V
10ns      1.8V       1.75V      1.85V
[Falling Waveform]
R_fixture= 50.000
V_fixture= 1.800
V_fixture_min= 1.750
V_fixture_max= 1.850
|time   V(typ)   V(min)   V(max)
0s        1.8V       1.75V      1.85V
386ps     1.8V       1.75V      1.841V
428ps     1.803V     1.75V      1.68V
504ps     1.78V      1.752V     1.113V
578ps     1.498V     1.749V     788.3mV
662ps     947.5mV    1.6V       715.9mV
728ps     733.3mV    1.328V     702.4mV
876ps     651.2mV    749mV      695.2mV
1.137ns   638.8mV    640.2mV    693.2mV
10ns      636.5mV    628.2mV    692.9mV
[Falling Waveform]
R_fixture= 50.000
V_fixture= 0.0
V_fixture_min= 0.0
V_fixture_max= 0.0
|time   V(typ)   V(min)   V(max)
0s        1.146V     1.099V     1.151V
384ps     1.143V     1.097V     1.14V
427ps     1.146V     1.097V     953.5mV
495ps     1.124V     1.098V     379.4mV
542ps     938.4mV    1.102V     136.3mV
610ps     400.2mV    1.033V     32.4mV
698ps     61.58mV    595.6mV    7.153mV
804ps     9.57mV     103.5mV    1.646mV
982ps     1.256mV    6.086mV    289.2uV
10ns      1.883uV    9.238uV    902.3nV
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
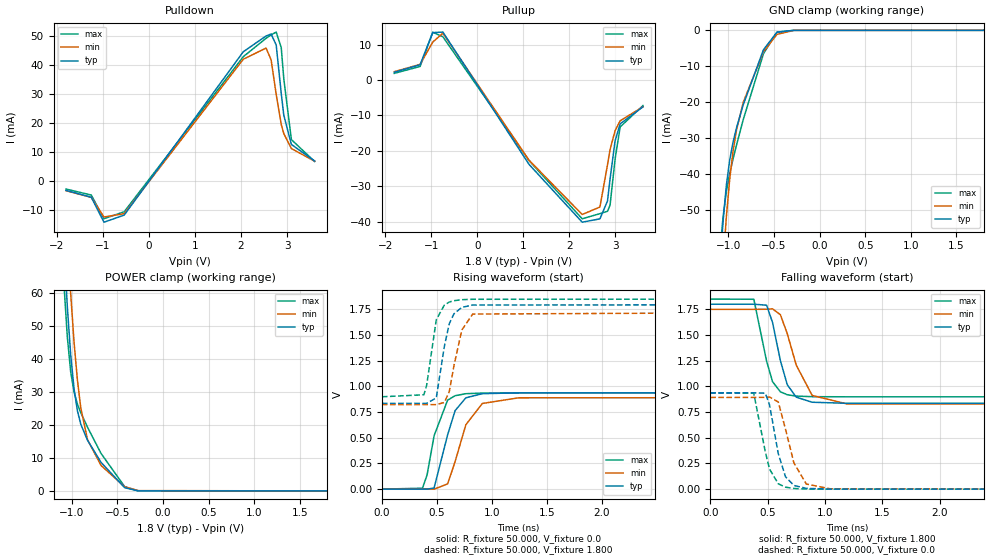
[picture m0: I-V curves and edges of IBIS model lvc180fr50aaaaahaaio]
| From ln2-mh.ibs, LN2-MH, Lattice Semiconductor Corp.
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|   Model lvc180fr50aaaaahaaio
[Model] lvc180fr50aaaaahaaio
| Clamp models do not include dynamic input termination. Please refer to
| the lvc180axxxaaaaahaain model for input termination.
Model_type I/O
Polarity   Non-Inverting
Enable   Active-Low
Vinl =  0.630V
Vinh =  1.170V
Vmeas =  0.900V
Cref =  0.0F
Rref =  1.000M
Vref =  0.0V
C_comp   2.000pF   1.500pF   2.500pF
[Temperature Range]   25.000   0.125k   -40.000
[Voltage Range]   1.800V   1.750V   1.850V
[C Comp Corner]
C_comp   2.000pF   1.500pF   2.500pF
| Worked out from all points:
|   slope of the pulldown table from 0 to 0.27 V, typ, clamps not added: 42.9 ohm
|   slope of the pullup table from 0 to 0.27 V, typ, clamps not added: 44.7 ohm
|   GND clamp passes 1 mA (typ) near -0.49 V on its own axis
|   POWER clamp passes 1 mA (typ) near -0.42 V on its own axis
|   rising waveform, R_fixture 50.000, V_fixture 0.0: 20-80 % time 127ps typ, 160ps min, 110ps max; typ from 0 V to 0.938 V
|   rising waveform, R_fixture 50.000, V_fixture 1.800: 20-80 % time 87.8ps typ, 107ps min, 80.7ps max; typ from 0.835 V to 1.8 V
|   falling waveform, R_fixture 50.000, V_fixture 1.800: 20-80 % time 121ps typ, 162ps min, 101ps max; typ from 1.8 V to 0.835 V
|   falling waveform, R_fixture 50.000, V_fixture 0.0: 20-80 % time 102ps typ, 125ps min, 98.2ps max; typ from 0.937 V to 0 V
[Pulldown]
|Voltage   I(typ)   I(min)   I(max)
-1.8V     -3.205mA   -3.321mA   -2.748mA
-1.25V    -5.576mA   -5.625mA   -4.818mA
-975mV    -14.17mA   -12.38mA   -12.97mA
-535mV    -11.72mA   -11.24mA   -10.57mA
2.05V     44.54mA    41.97mA    42.84mA
2.545V    49.98mA    45.81mA    49.18mA
2.655V    50.66mA    41.76mA    50.38mA
2.765V    46.89mA    29.84mA    51.32mA
2.875V    30.14mA    19.51mA    45.95mA
2.93V     22.69mA    16.35mA    35.23mA
3.095V    12.61mA    11.2mA     14.28mA
3.6V      6.912mA    6.835mA    6.723mA
[Pullup]
|Voltage   I(typ)   I(min)   I(max)
-1.8V     2.179mA    2.351mA    1.868mA
-1.24V    4.296mA    4.402mA    3.813mA
-965mV    13.36mA    10.69mA    13.48mA
-745mV    13.51mA    13.2mA     12.19mA
1.125V    -23.79mA   -22.61mA   -22.73mA
2.28V     -40.11mA   -37.94mA   -39.15mA
2.665V    -39.17mA   -35.83mA   -37.7mA
2.83V     -34.09mA   -23.89mA   -37.03mA
2.885V    -27.92mA   -19.64mA   -35.32mA
2.995V    -17.13mA   -14.27mA   -22.24mA
3.105V    -12.36mA   -11.5mA    -13.23mA
3.6V      -7.572mA   -7.557mA   -7.214mA
[GND_clamp]
|Voltage   I(typ)   I(min)   I(max)
-1.8V     -570.9mA   -571.8mA   -572.9mA
-1.097V   -67.54mA   -81.64mA   -63.35mA
-1.06V    -53.45mA   -65.42mA   -52.13mA
-1.023V   -43.13mA   -51.95mA   -44.86mA
-986mV    -36.04mA   -41.41mA   -39.83mA
-949mV    -31.06mA   -33.56mA   -35.72mA
-912mV    -27.18mA   -27.83mA   -31.97mA
-838mV    -20.73mA   -20.06mA   -24.86mA
-616mV    -5.403mA   -5.958mA   -6.517mA
-468mV    -530.3uA   -1.122mA   -495.6uA
-283mV    -1.808uA   -19.61uA   -457.7nA
1.8V      0A         0A         0A
[POWER_clamp]
|Voltage   I(typ)   I(min)   I(max)
-1.789V   617.6mA    624.8mA    616.1mA
-1.086V   74.43mA    97.5mA     62.76mA
-1.049V   55.98mA    77.5mA     46.8mA
-1.012V   41.32mA    59.89mA    36.12mA
-975mV    30.91mA    45.13mA    29.96mA
-938mV    24.29mA    33.57mA    26.33mA
-901mV    20.21mA    25.16mA    23.7mA
-827mV    15.35mA    15.5mA     19.29mA
-679mV    8.657mA    7.724mA    11.36mA
-420mV    977.9uA    1.256mA    1.313mA
-272mV    22.92uA    106.7uA    14.08uA
1.8V      0A         0A         0A
[Ramp]
| variable   typ   min   max
dV/dt_r   0.563/0.127n   0.536/0.160n   0.562/0.110n
dV/dt_f   0.579/0.121n   0.556/0.163n   0.571/0.101n
R_load = 50.000
[Rising Waveform]
R_fixture= 50.000
V_fixture= 0.0
V_fixture_min= 0.0
V_fixture_max= 0.0
|time   V(typ)   V(min)   V(max)
0s        2.404uV    12.25uV    1.1uV
369ps     71.87uV    58.48uV    8.909mV
411ps     -495.8uV   80.61uV    136.3mV
475ps     11.17mV    -333.7uV   519.2mV
598ps     527.8mV    50.69mV    865.8mV
666ps     763.7mV    267.7mV    909.3mV
764ps     888.9mV    626.7mV    928.9mV
914ps     929.1mV    833.7mV    935mV
1.244ns   937.1mV    888.8mV    936.2mV
10ns      937.5mV    892.5mV    936.2mV
[Rising Waveform]
R_fixture= 50.000
V_fixture= 1.800
V_fixture_min= 1.750
V_fixture_max= 1.850
|time   V(typ)   V(min)   V(max)
0s        834.8mV    822.8mV    898.8mV
382ps     834.7mV    822.8mV    918.4mV
407ps     834.5mV    822.8mV    1.008V
495ps     888mV      822.8mV    1.649V
568ps     1.387V     843.3mV    1.791V
613ps     1.61V      947.9mV    1.821V
656ps     1.707V     1.203V     1.834V
727ps     1.769V     1.548V     1.844V
826ps     1.792V     1.704V     1.848V
10ns      1.8V       1.75V      1.85V
[Falling Waveform]
R_fixture= 50.000
V_fixture= 1.800
V_fixture_min= 1.750
V_fixture_max= 1.850
|time   V(typ)   V(min)   V(max)
0s        1.8V       1.75V      1.85V
380ps     1.8V       1.75V      1.848V
491ps     1.79V      1.751V     1.247V
543ps     1.622V     1.755V     1.046V
611ps     1.252V     1.698V     947.8mV
671ps     1.017V     1.514V     918.8mV
749ps     895.4mV    1.208V     905.6mV
888ps     846mV      912mV      900.1mV
1.191ns   835.6mV    829.5mV    898.9mV
10ns      834.8mV    822.8mV    898.8mV
[Falling Waveform]
R_fixture= 50.000
V_fixture= 0.0
V_fixture_min= 0.0
V_fixture_max= 0.0
|time   V(typ)   V(min)   V(max)
0s        937.5mV    892.5mV    936.2mV
379ps     937.4mV    892.4mV    934.5mV
480ps     934.1mV    893.5mV    363.2mV
517ps     818.7mV    896.4mV    194.9mV
593ps     344.7mV    848.3mV    52.14mV
656ps     120.3mV    582.3mV    19.26mV
729ps     35.95mV    255.1mV    6.662mV
837ps     7.766mV    49.95mV    1.629mV
1.047ns   785.2uV    3.599mV    195.6uV
10ns      2.519uV    12.42uV    1.191uV
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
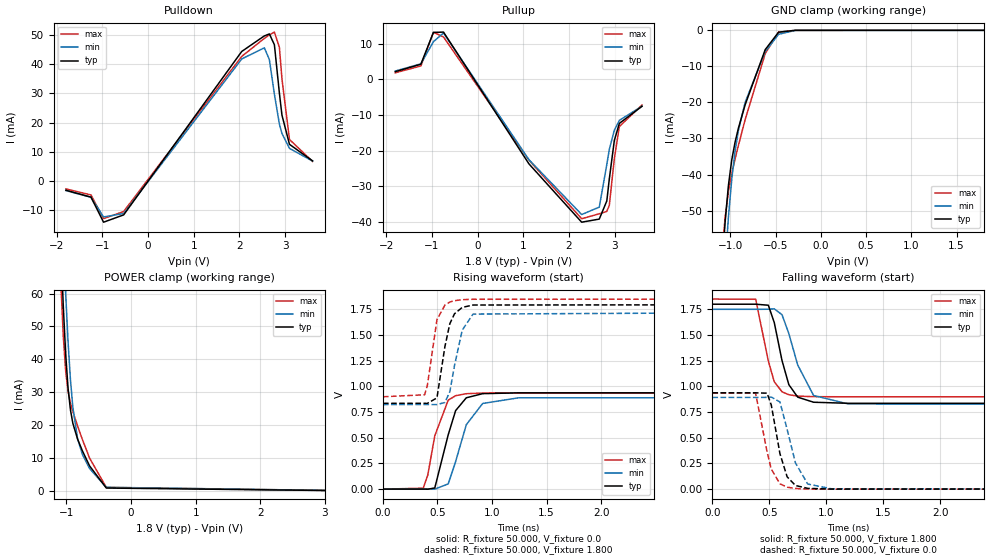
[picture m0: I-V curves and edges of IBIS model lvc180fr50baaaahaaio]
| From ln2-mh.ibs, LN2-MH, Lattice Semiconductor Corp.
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|   Model lvc180fr50baaaahaaio
[Model] lvc180fr50baaaahaaio
| Clamp models do not include dynamic input termination. Please refer to
| the lvc180axxxbaaaahaain model for input termination.
Model_type I/O
Polarity   Non-Inverting
Enable   Active-Low
Vinl =  0.630V
Vinh =  1.170V
Vmeas =  0.900V
Cref =  0.0F
Rref =  1.000M
Vref =  0.0V
C_comp   2.000pF   1.500pF   2.500pF
[Temperature Range]   25.000   0.125k   -40.000
[Voltage Range]   1.800V   1.750V   1.850V
[C Comp Corner]
C_comp   2.000pF   1.500pF   2.500pF
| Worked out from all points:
|   slope of the pulldown table from 0 to 0.27 V, typ, clamps not added: 42.9 ohm
|   slope of the pullup table from 0 to 0.27 V, typ, clamps not added: 45.5 ohm
|   GND clamp passes 1 mA (typ) near -0.50 V on its own axis
|   POWER clamp passes 1 mA (typ) near -0.40 V on its own axis
|   rising waveform, R_fixture 50.000, V_fixture 0.0: 20-80 % time 127ps typ, 160ps min, 110ps max; typ from 0 V to 0.938 V
|   rising waveform, R_fixture 50.000, V_fixture 1.800: 20-80 % time 87.8ps typ, 107ps min, 80.7ps max; typ from 0.835 V to 1.8 V
|   falling waveform, R_fixture 50.000, V_fixture 1.800: 20-80 % time 121ps typ, 162ps min, 101ps max; typ from 1.8 V to 0.835 V
|   falling waveform, R_fixture 50.000, V_fixture 0.0: 20-80 % time 102ps typ, 125ps min, 98.2ps max; typ from 0.937 V to 0 V
[Pulldown]
|Voltage   I(typ)   I(min)   I(max)
-1.8V     -3.201mA   -3.316mA   -2.744mA
-1.25V    -5.569mA   -5.616mA   -4.811mA
-975mV    -14.15mA   -12.35mA   -12.94mA
-535mV    -11.65mA   -11.18mA   -10.5mA
2.05V     44.35mA    41.79mA    42.66mA
2.545V    49.68mA    45.59mA    48.83mA
2.655V    50.36mA    41.57mA    50.03mA
2.765V    46.65mA    29.71mA    50.99mA
2.875V    29.99mA    19.42mA    45.69mA
2.93V     22.57mA    16.27mA    35.05mA
3.095V    12.53mA    11.14mA    14.19mA
3.6V      6.866mA    6.794mA    6.674mA
[Pullup]
|Voltage   I(typ)   I(min)   I(max)
-1.8V     2.133mA    2.309mA    1.821mA
-1.24V    4.215mA    4.333mA    3.727mA
-965mV    13.12mA    10.53mA    13.16mA
-745mV    13.21mA    12.97mA    11.84mA
1.125V    -23.68mA   -22.51mA   -22.63mA
2.28V     -40.02mA   -37.88mA   -39.05mA
2.665V    -39.15mA   -35.8mA    -37.67mA
2.83V     -34.07mA   -23.88mA   -37mA
2.885V    -27.9mA    -19.63mA   -35.3mA
2.995V    -17.12mA   -14.26mA   -22.22mA
3.105V    -12.35mA   -11.5mA    -13.22mA
3.6V      -7.568mA   -7.552mA   -7.21mA
[GND_clamp]
|Voltage   I(typ)   I(min)   I(max)
-1.8V     -570.8mA   -571.7mA   -572.8mA
-1.097V   -67.45mA   -81.54mA   -63.25mA
-1.06V    -53.36mA   -65.33mA   -52.04mA
-1.023V   -43.04mA   -51.86mA   -44.77mA
-986mV    -35.95mA   -41.32mA   -39.74mA
-949mV    -30.97mA   -33.48mA   -35.64mA
-912mV    -27.1mA    -27.74mA   -31.88mA
-838mV    -20.66mA   -19.98mA   -24.78mA
-616mV    -5.345mA   -5.898mA   -6.456mA
-468mV    -515.9uA   -1.096mA   -482.9uA
-283mV    -1.482uA   -17.52uA   -322.5nA
1.8V      0A         0A         0A
[POWER_clamp]
|Voltage   I(typ)   I(min)   I(max)
-1.789V   617.6mA    624.8mA    616.1mA
-1.086V   74.57mA    97.6mA     62.94mA
-1.049V   56.15mA    77.62mA    47.03mA
-1.012V   41.52mA    60.02mA    36.39mA
-975mV    31.15mA    45.29mA    30.27mA
-938mV    24.56mA    33.75mA    26.65mA
-901mV    20.5mA     25.36mA    24.04mA
-827mV    15.64mA    15.72mA    19.63mA
-753mV    12.1mA     11mA       15.55mA
-642mV    7.512mA    6.704mA    9.896mA
-383mV    772.8uA    998.1uA    969uA
3.6V      -108.1uA   -110.5uA   -109.2uA
[Ramp]
| variable   typ   min   max
dV/dt_r   0.563/0.127n   0.536/0.160n   0.562/0.110n
dV/dt_f   0.579/0.121n   0.556/0.163n   0.571/0.101n
R_load = 50.000
[Rising Waveform]
R_fixture= 50.000
V_fixture= 0.0
V_fixture_min= 0.0
V_fixture_max= 0.0
|time   V(typ)   V(min)   V(max)
0s        2.404uV    12.25uV    1.1uV
369ps     71.87uV    58.48uV    8.909mV
411ps     -495.8uV   80.61uV    136.3mV
475ps     11.17mV    -333.7uV   519.2mV
598ps     527.8mV    50.69mV    865.8mV
666ps     763.7mV    267.7mV    909.3mV
764ps     888.9mV    626.7mV    928.9mV
914ps     929.1mV    833.7mV    935mV
1.244ns   937.1mV    888.8mV    936.2mV
10ns      937.5mV    892.5mV    936.2mV
[Rising Waveform]
R_fixture= 50.000
V_fixture= 1.800
V_fixture_min= 1.750
V_fixture_max= 1.850
|time   V(typ)   V(min)   V(max)
0s        834.8mV    822.8mV    898.8mV
382ps     834.7mV    822.8mV    918.4mV
407ps     834.5mV    822.8mV    1.008V
495ps     888mV      822.8mV    1.649V
568ps     1.387V     843.3mV    1.791V
613ps     1.61V      947.9mV    1.821V
656ps     1.707V     1.203V     1.834V
727ps     1.769V     1.548V     1.844V
826ps     1.792V     1.704V     1.848V
10ns      1.8V       1.75V      1.85V
[Falling Waveform]
R_fixture= 50.000
V_fixture= 1.800
V_fixture_min= 1.750
V_fixture_max= 1.850
|time   V(typ)   V(min)   V(max)
0s        1.8V       1.75V      1.85V
380ps     1.8V       1.75V      1.848V
491ps     1.79V      1.751V     1.247V
543ps     1.622V     1.755V     1.046V
611ps     1.252V     1.698V     947.8mV
671ps     1.017V     1.514V     918.8mV
749ps     895.4mV    1.208V     905.6mV
888ps     846mV      912mV      900.1mV
1.191ns   835.6mV    829.5mV    898.9mV
10ns      834.8mV    822.8mV    898.8mV
[Falling Waveform]
R_fixture= 50.000
V_fixture= 0.0
V_fixture_min= 0.0
V_fixture_max= 0.0
|time   V(typ)   V(min)   V(max)
0s        937.5mV    892.5mV    936.2mV
379ps     937.4mV    892.4mV    934.5mV
480ps     934.1mV    893.5mV    363.2mV
517ps     818.7mV    896.4mV    194.9mV
593ps     344.7mV    848.3mV    52.14mV
656ps     120.3mV    582.3mV    19.26mV
729ps     35.95mV    255.1mV    6.662mV
837ps     7.766mV    49.95mV    1.629mV
1.047ns   785.2uV    3.599mV    195.6uV
10ns      2.519uV    12.42uV    1.191uV
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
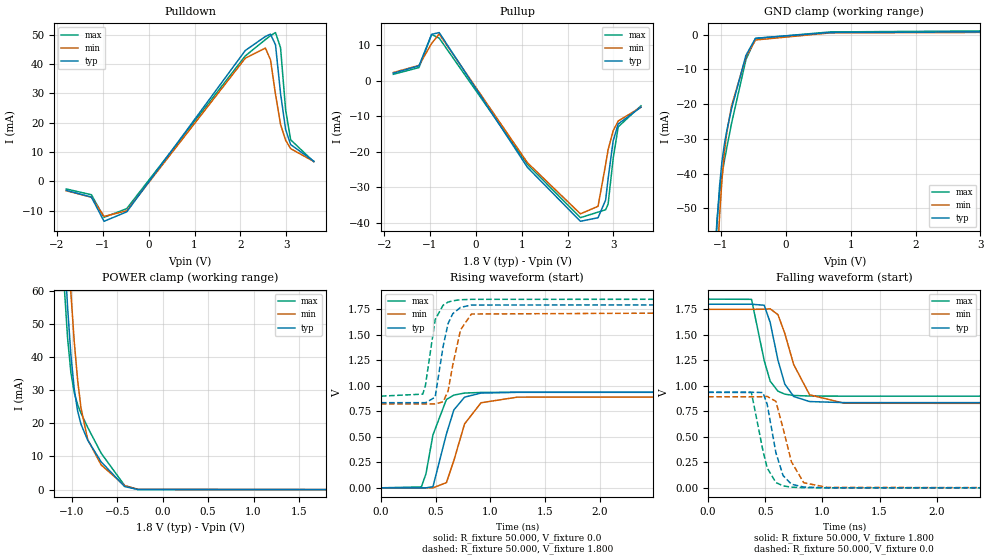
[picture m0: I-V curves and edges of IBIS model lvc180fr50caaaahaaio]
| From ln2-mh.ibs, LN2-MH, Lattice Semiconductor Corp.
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|   Model lvc180fr50caaaahaaio
[Model] lvc180fr50caaaahaaio
| Clamp models do not include dynamic input termination. Please refer to
| the lvc180axxxcaaaahaain model for input termination.
Model_type I/O
Polarity   Non-Inverting
Enable   Active-Low
Vinl =  0.630V
Vinh =  1.170V
Vmeas =  0.900V
Cref =  0.0F
Rref =  1.000M
Vref =  0.0V
C_comp   2.000pF   1.500pF   2.500pF
[Temperature Range]   25.000   0.125k   -40.000
[Voltage Range]   1.800V   1.750V   1.850V
[C Comp Corner]
C_comp   2.000pF   1.500pF   2.500pF
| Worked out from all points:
|   slope of the pulldown table from 0 to 0.27 V, typ, clamps not added: 44.9 ohm
|   slope of the pullup table from 0 to 0.27 V, typ, clamps not added: 44.8 ohm
|   GND clamp passes 1 mA (typ) near -0.47 V on its own axis
|   POWER clamp passes 1 mA (typ) near -0.42 V on its own axis
|   rising waveform, R_fixture 50.000, V_fixture 0.0: 20-80 % time 127ps typ, 160ps min, 110ps max; typ from 0 V to 0.938 V
|   rising waveform, R_fixture 50.000, V_fixture 1.800: 20-80 % time 87.8ps typ, 107ps min, 80.7ps max; typ from 0.835 V to 1.8 V
|   falling waveform, R_fixture 50.000, V_fixture 1.800: 20-80 % time 121ps typ, 162ps min, 101ps max; typ from 1.8 V to 0.835 V
|   falling waveform, R_fixture 50.000, V_fixture 0.0: 20-80 % time 102ps typ, 125ps min, 98.2ps max; typ from 0.937 V to 0 V
[Pulldown]
|Voltage   I(typ)   I(min)   I(max)
-1.8V     -3.079mA   -3.208mA   -2.604mA
-1.25V    -5.37mA    -5.445mA   -4.579mA
-975mV    -13.65mA   -11.99mA   -12.31mA
-480mV    -10.42mA   -10.07mA   -9.325mA
2.105V    44.66mA    42.03mA    42.82mA
2.545V    49.47mA    45.49mA    48.41mA
2.655V    50.26mA    41.54mA    49.73mA
2.765V    46.62mA    29.7mA     50.8mA
2.875V    30mA       19.43mA    45.62mA
2.985V    17.73mA    14.03mA    24.48mA
3.095V    12.55mA    11.15mA    14.19mA
3.6V      6.876mA    6.8mA      6.678mA
[Pullup]
|Voltage   I(typ)   I(min)   I(max)
-1.8V     2.144mA    2.316mA    1.824mA
-1.24V    4.226mA    4.338mA    3.722mA
-965mV    13.09mA    10.52mA    13.03mA
-800mV    13.59mA    13.2mA     12.04mA
1.125V    -24.42mA   -23.11mA   -23.58mA
2.28V     -39.63mA   -37.53mA   -38.61mA
2.665V    -38.63mA   -35.4mA    -37.04mA
2.83V     -33.63mA   -23.61mA   -36.38mA
2.885V    -27.55mA   -19.4mA    -34.71mA
2.995V    -16.89mA   -14.09mA   -21.87mA
3.105V    -12.18mA   -11.35mA   -12.99mA
3.6V      -7.446mA   -7.445mA   -7.067mA
[GND_clamp]
|Voltage   I(typ)   I(min)   I(max)
-1.8V     -571mA     -571.9mA   -573mA
-1.097V   -67.89mA   -81.9mA    -63.82mA
-1.06V    -53.86mA   -65.72mA   -52.69mA
-1.023V   -43.6mA    -52.29mA   -45.48mA
-986mV    -36.55mA   -41.78mA   -40.47mA
-949mV    -31.59mA   -33.97mA   -36.38mA
-912mV    -27.73mA   -28.25mA   -32.63mA
-838mV    -21.28mA   -20.51mA   -25.51mA
-616mV    -5.929mA   -6.39mA    -7.151mA
-468mV    -1.006mA   -1.514mA   -1.077mA
679mV     636.6uA    525.1uA    801uA
3.6V      859.5uA    698.9uA    1.171mA
[POWER_clamp]
|Voltage   I(typ)   I(min)   I(max)
-1.789V   616.8mA    624.1mA    614.9mA
-1.086V   73.72mA    96.92mA    61.82mA
-1.049V   55.3mA     76.94mA    45.93mA
-1.012V   40.68mA    59.35mA    35.33mA
-975mV    30.32mA    44.62mA    29.25mA
-938mV    23.76mA    33.09mA    25.68mA
-901mV    19.73mA    24.71mA    23.1mA
-827mV    14.94mA    15.12mA    18.78mA
-679mV    8.384mA    7.465mA    11.01mA
-420mV    917.4uA    1.181mA    1.232mA
-272mV    19.37uA    92.48uA    11.5uA
1.8V      0A         0A         0A
[Ramp]
| variable   typ   min   max
dV/dt_r   0.563/0.127n   0.536/0.160n   0.562/0.110n
dV/dt_f   0.579/0.121n   0.556/0.163n   0.571/0.101n
R_load = 50.000
[Rising Waveform]
R_fixture= 50.000
V_fixture= 0.0
V_fixture_min= 0.0
V_fixture_max= 0.0
|time   V(typ)   V(min)   V(max)
0s        2.404uV    12.25uV    1.1uV
369ps     71.87uV    58.48uV    8.909mV
411ps     -495.8uV   80.61uV    136.3mV
475ps     11.17mV    -333.7uV   519.2mV
598ps     527.8mV    50.69mV    865.8mV
666ps     763.7mV    267.7mV    909.3mV
764ps     888.9mV    626.7mV    928.9mV
914ps     929.1mV    833.7mV    935mV
1.244ns   937.1mV    888.8mV    936.2mV
10ns      937.5mV    892.5mV    936.2mV
[Rising Waveform]
R_fixture= 50.000
V_fixture= 1.800
V_fixture_min= 1.750
V_fixture_max= 1.850
|time   V(typ)   V(min)   V(max)
0s        834.8mV    822.8mV    898.8mV
382ps     834.7mV    822.8mV    918.4mV
407ps     834.5mV    822.8mV    1.008V
495ps     888mV      822.8mV    1.649V
568ps     1.387V     843.3mV    1.791V
613ps     1.61V      947.9mV    1.821V
656ps     1.707V     1.203V     1.834V
727ps     1.769V     1.548V     1.844V
826ps     1.792V     1.704V     1.848V
10ns      1.8V       1.75V      1.85V
[Falling Waveform]
R_fixture= 50.000
V_fixture= 1.800
V_fixture_min= 1.750
V_fixture_max= 1.850
|time   V(typ)   V(min)   V(max)
0s        1.8V       1.75V      1.85V
380ps     1.8V       1.75V      1.848V
491ps     1.79V      1.751V     1.247V
543ps     1.622V     1.755V     1.046V
611ps     1.252V     1.698V     947.8mV
671ps     1.017V     1.514V     918.8mV
749ps     895.4mV    1.208V     905.6mV
888ps     846mV      912mV      900.1mV
1.191ns   835.6mV    829.5mV    898.9mV
10ns      834.8mV    822.8mV    898.8mV
[Falling Waveform]
R_fixture= 50.000
V_fixture= 0.0
V_fixture_min= 0.0
V_fixture_max= 0.0
|time   V(typ)   V(min)   V(max)
0s        937.5mV    892.5mV    936.2mV
379ps     937.4mV    892.4mV    934.5mV
480ps     934.1mV    893.5mV    363.2mV
517ps     818.7mV    896.4mV    194.9mV
593ps     344.7mV    848.3mV    52.14mV
656ps     120.3mV    582.3mV    19.26mV
729ps     35.95mV    255.1mV    6.662mV
837ps     7.766mV    49.95mV    1.629mV
1.047ns   785.2uV    3.599mV    195.6uV
10ns      2.519uV    12.42uV    1.191uV
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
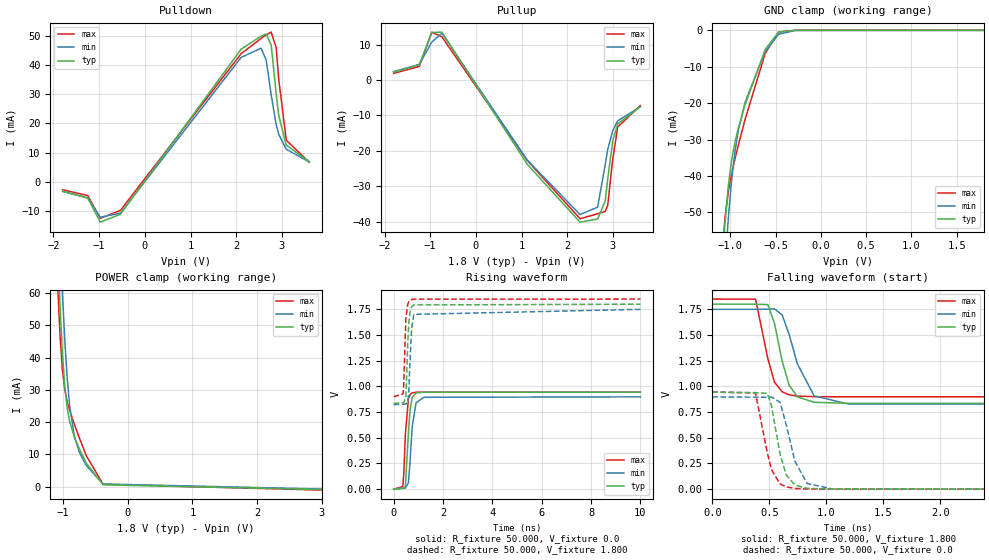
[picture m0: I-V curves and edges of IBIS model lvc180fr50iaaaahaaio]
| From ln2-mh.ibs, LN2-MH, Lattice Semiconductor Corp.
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|   Model lvc180fr50iaaaahaaio
[Model] lvc180fr50iaaaahaaio
| Clamp models do not include dynamic input termination. Please refer to
| the lvc180axxxiaaaahaain model for input termination.
Model_type I/O
Polarity   Non-Inverting
Enable   Active-Low
Vinl =  0.630V
Vinh =  1.170V
Vmeas =  0.900V
Cref =  0.0F
Rref =  1.000M
Vref =  0.0V
C_comp   2.000pF   1.500pF   2.500pF
[Temperature Range]   25.000   0.125k   -40.000
[Voltage Range]   1.800V   1.750V   1.850V
[C Comp Corner]
C_comp   2.000pF   1.500pF   2.500pF
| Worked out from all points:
|   slope of the pulldown table from 0 to 0.27 V, typ, clamps not added: 43.5 ohm
|   slope of the pullup table from 0 to 0.27 V, typ, clamps not added: 44.8 ohm
|   GND clamp passes 1 mA (typ) near -0.50 V on its own axis
|   POWER clamp passes 1 mA (typ) near -0.41 V on its own axis
|   rising waveform, R_fixture 50.000, V_fixture 0.0: 20-80 % time 126ps typ, 159ps min, 109ps max; typ from 0 V to 0.944 V
|   rising waveform, R_fixture 50.000, V_fixture 1.800: 20-80 % time 86.8ps typ, 107ps min, 79.3ps max; typ from 0.835 V to 1.8 V
|   falling waveform, R_fixture 50.000, V_fixture 1.800: 20-80 % time 121ps typ, 162ps min, 101ps max; typ from 1.8 V to 0.835 V
|   falling waveform, R_fixture 50.000, V_fixture 0.0: 20-80 % time 102ps typ, 125ps min, 98.6ps max; typ from 0.944 V to 0 V
[Pulldown]
|Voltage   I(typ)   I(min)   I(max)
-1.8V     -3.152mA   -3.27mA    -2.686mA
-1.25V    -5.466mA   -5.525mA   -4.686mA
-975mV    -13.79mA   -12.1mA    -12.47mA
-535mV    -11.06mA   -10.7mA    -9.758mA
2.105V    45.39mA    42.58mA    43.85mA
2.545V    49.93mA    45.77mA    49.12mA
2.655V    50.61mA    41.73mA    50.33mA
2.765V    46.86mA    29.81mA    51.28mA
2.875V    30.12mA    19.5mA     45.92mA
2.93V     22.67mA    16.33mA    35.21mA
3.095V    12.6mA     11.19mA    14.27mA
3.6V      6.906mA    6.828mA    6.716mA
[Pullup]
|Voltage   I(typ)   I(min)   I(max)
-1.8V     2.18mA     2.351mA    1.868mA
-1.24V    4.297mA    4.403mA    3.814mA
-965mV    13.36mA    10.69mA    13.48mA
-745mV    13.51mA    13.2mA     12.19mA
1.125V    -23.78mA   -22.6mA    -22.72mA
2.28V     -40.11mA   -37.95mA   -39.13mA
2.665V    -39.2mA    -35.86mA   -37.73mA
2.83V     -34.14mA   -23.93mA   -37.06mA
2.885V    -27.98mA   -19.67mA   -35.38mA
2.995V    -17.15mA   -14.28mA   -22.31mA
3.105V    -12.37mA   -11.51mA   -13.25mA
3.6V      -7.574mA   -7.558mA   -7.216mA
[GND_clamp]
|Voltage   I(typ)   I(min)   I(max)
-1.8V     -569.8mA   -570.8mA   -571.6mA
-1.097V   -66.86mA   -81.02mA   -62.54mA
-1.06V    -52.83mA   -64.84mA   -51.42mA
-1.023V   -42.57mA   -51.42mA   -44.23mA
-986mV    -35.54mA   -40.92mA   -39.25mA
-949mV    -30.61mA   -33.13mA   -35.19mA
-912mV    -26.78mA   -27.43mA   -31.48mA
-838mV    -20.4mA    -19.75mA   -24.45mA
-616mV    -5.27mA    -5.819mA   -6.352mA
-468mV    -506.6uA   -1.081mA   -470.6uA
-283mV    -1.427uA   -17.24uA   -284.7nA
1.8V      0A         0A         0A
[POWER_clamp]
|Voltage   I(typ)   I(min)   I(max)
-1.789V   617.6mA    624.8mA    616.1mA
-1.086V   74.45mA    97.52mA    62.79mA
-1.049V   56mA       77.52mA    46.83mA
-1.012V   41.34mA    59.91mA    36.16mA
-975mV    30.94mA    45.16mA    30mA
-938mV    24.33mA    33.6mA     26.37mA
-901mV    20.25mA    25.2mA     23.75mA
-827mV    15.39mA    15.54mA    19.34mA
-753mV    11.85mA    10.81mA    15.26mA
-642mV    7.266mA    6.521mA    9.605mA
-383mV    595.8uA    860.9uA    753.9uA
3.6V      -1.113mA   -985.8uA   -1.346mA
[Ramp]
| variable   typ   min   max
dV/dt_r   0.566/0.126n   0.539/0.159n   0.567/0.109n
dV/dt_f   0.579/0.121n   0.556/0.163n   0.571/0.101n
R_load = 50.000
[Rising Waveform]
R_fixture= 50.000
V_fixture= 0.0
V_fixture_min= 0.0
V_fixture_max= 0.0
|time   V(typ)   V(min)   V(max)
0s        2.404uV    12.25uV    1.1uV
370ps     10.64mV    7.236mV    25.21mV
413ps     10.96mV    8.894mV    160.9mV
474ps     21.84mV    9.668mV    532.7mV
599ps     547.7mV    63.11mV    881.1mV
666ps     777.9mV    279.6mV    920.9mV
755ps     893.9mV    614.8mV    937.6mV
908ps     936.1mV    839.8mV    943.4mV
1.223ns   943.4mV    894.2mV    944.4mV
10ns      943.8mV    898.2mV    944.5mV
[Rising Waveform]
R_fixture= 50.000
V_fixture= 1.800
V_fixture_min= 1.750
V_fixture_max= 1.850
|time   V(typ)   V(min)   V(max)
0s        834.8mV    822.8mV    898.8mV
382ps     840.8mV    827.1mV    926.8mV
407ps     840.8mV    827.6mV    1.017V
495ps     895.3mV    828.4mV    1.658V
567ps     1.389V     848.5mV    1.795V
613ps     1.617V     954.9mV    1.824V
656ps     1.713V     1.21V      1.837V
726ps     1.772V     1.551V     1.845V
817ps     1.793V     1.701V     1.849V
10ns      1.8V       1.75V      1.85V
[Falling Waveform]
R_fixture= 50.000
V_fixture= 1.800
V_fixture_min= 1.750
V_fixture_max= 1.850
|time   V(typ)   V(min)   V(max)
0s        1.8V       1.75V      1.85V
379ps     1.8V       1.75V      1.849V
486ps     1.796V     1.751V     1.273V
544ps     1.617V     1.755V     1.043V
612ps     1.247V     1.696V     947.1mV
673ps     1.012V     1.506V     918.3mV
746ps     897.8mV    1.219V     905.9mV
893ps     845.4mV    907.5mV    900mV
1.19ns    835.6mV    829.6mV    898.9mV
10ns      834.8mV    822.8mV    898.8mV
[Falling Waveform]
R_fixture= 50.000
V_fixture= 0.0
V_fixture_min= 0.0
V_fixture_max= 0.0
|time   V(typ)   V(min)   V(max)
0s        943.8mV    898.2mV    944.4mV
378ps     939.4mV    895.6mV    936.9mV
482ps     932.1mV    894.7mV    352.5mV
519ps     808.4mV    897.3mV    188.1mV
594ps     339.7mV    846.2mV    51.3mV
647ps     140.8mV    629.3mV    22.13mV
724ps     38.97mV    272.6mV    7.15mV
831ps     8.396mV    54.78mV    1.756mV
1.05ns    765uV      3.497mV    191.4uV
10ns      2.521uV    12.42uV    1.191uV
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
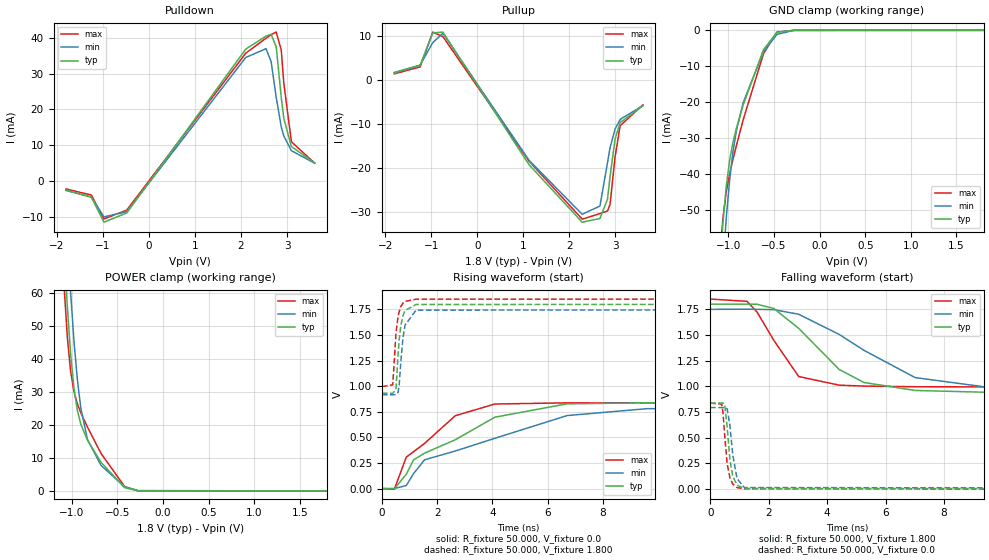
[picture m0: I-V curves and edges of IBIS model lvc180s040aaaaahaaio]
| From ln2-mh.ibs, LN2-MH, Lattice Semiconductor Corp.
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|   Model lvc180s040aaaaahaaio
[Model] lvc180s040aaaaahaaio
| Clamp models do not include dynamic input termination. Please refer to
| the lvc180axxxaaaaahaain model for input termination.
Model_type I/O
Polarity   Non-Inverting
Enable   Active-Low
Vinl =  0.630V
Vinh =  1.170V
Vmeas =  0.900V
Cref =  0.0F
Rref =  1.000M
Vref =  0.0V
C_comp   2.000pF   1.500pF   2.500pF
[Temperature Range]   25.000   0.125k   -40.000
[Voltage Range]   1.800V   1.750V   1.850V
[C Comp Corner]
C_comp   2.000pF   1.500pF   2.500pF
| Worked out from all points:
|   slope of the pulldown table from 0 to 0.27 V, typ, clamps not added: 53 ohm
|   slope of the pullup table from 0 to 0.27 V, typ, clamps not added: 55.2 ohm
|   GND clamp passes 1 mA (typ) near -0.49 V on its own axis
|   POWER clamp passes 1 mA (typ) near -0.42 V on its own axis
|   rising waveform, R_fixture 50.000, V_fixture 0.0: 20-80 % time 2.98ns typ, 4.41ns min, 1.81ns max; typ from 0 V to 0.838 V
|   rising waveform, R_fixture 50.000, V_fixture 1.800: 20-80 % time 164ps typ, 179ps min, 156ps max; typ from 0.93 V to 1.8 V
|   falling waveform, R_fixture 50.000, V_fixture 1.800: 20-80 % time 1.91ns typ, 3.1ns min, 1.08ns max; typ from 1.8 V to 0.93 V
|   falling waveform, R_fixture 50.000, V_fixture 0.0: 20-80 % time 175ps typ, 195ps min, 164ps max; typ from 0.838 V to 0 V
[Pulldown]
|Voltage   I(typ)   I(min)   I(max)
-1.8V     -2.482mA   -2.555mA   -2.152mA
-1.25V    -4.401mA   -4.43mA    -3.829mA
-975mV    -11.41mA   -9.932mA   -10.5mA
-480mV    -8.83mA    -8.472mA   -8.052mA
2.105V    36.85mA    34.5mA     35.7mA
2.545V    40.44mA    36.95mA    39.88mA
2.655V    40.95mA    33.36mA    40.84mA
2.765V    37.49mA    23.39mA    41.57mA
2.875V    23.42mA    15.13mA    36.57mA
2.93V     17.54mA    12.62mA    27.39mA
3.095V    9.664mA    8.526mA    11mA
3.6V      5.132mA    5.017mA    5.056mA
[Pullup]
|Voltage   I(typ)   I(min)   I(max)
-1.8V     1.616mA    1.727mA    1.404mA
-1.24V    3.334mA    3.394mA    2.99mA
-965mV    10.72mA    8.506mA    10.9mA
-745mV    10.91mA    10.64mA    9.88mA
1.125V    -19.24mA   -18.24mA   -18.43mA
2.28V     -32.33mA   -30.53mA   -31.64mA
2.665V    -31.5mA    -28.66mA   -30.37mA
2.83V     -27.08mA   -18.79mA   -29.79mA
2.885V    -21.95mA   -15.36mA   -28.28mA
2.995V    -13.39mA   -11.13mA   -17.39mA
3.105V    -9.651mA   -8.942mA   -10.37mA
3.6V      -5.85mA    -5.79mA    -5.624mA
[GND_clamp]
|Voltage   I(typ)   I(min)   I(max)
-1.8V     -570.9mA   -571.8mA   -572.9mA
-1.097V   -67.54mA   -81.64mA   -63.35mA
-1.06V    -53.45mA   -65.42mA   -52.13mA
-1.023V   -43.13mA   -51.95mA   -44.86mA
-986mV    -36.04mA   -41.41mA   -39.83mA
-949mV    -31.06mA   -33.56mA   -35.72mA
-912mV    -27.18mA   -27.83mA   -31.97mA
-838mV    -20.73mA   -20.06mA   -24.86mA
-616mV    -5.403mA   -5.958mA   -6.517mA
-468mV    -530.3uA   -1.122mA   -495.6uA
-283mV    -1.808uA   -19.61uA   -457.7nA
1.8V      0A         0A         0A
[POWER_clamp]
|Voltage   I(typ)   I(min)   I(max)
-1.789V   617.6mA    624.8mA    616.1mA
-1.086V   74.43mA    97.5mA     62.76mA
-1.049V   55.98mA    77.5mA     46.8mA
-1.012V   41.32mA    59.89mA    36.12mA
-975mV    30.91mA    45.13mA    29.96mA
-938mV    24.29mA    33.57mA    26.33mA
-901mV    20.21mA    25.16mA    23.7mA
-827mV    15.35mA    15.5mA     19.29mA
-679mV    8.657mA    7.724mA    11.36mA
-420mV    977.9uA    1.256mA    1.313mA
-272mV    22.92uA    106.7uA    14.08uA
1.8V      0A         0A         0A
[Ramp]
| variable   typ   min   max
dV/dt_r   0.503/2.986n   0.476/4.418n   0.502/1.814n
dV/dt_f   0.522/1.915n   0.500/3.122n   0.513/1.079n
R_load = 50.000
[Rising Waveform]
R_fixture= 50.000
V_fixture= 0.0
V_fixture_min= 0.0
V_fixture_max= 0.0
|time   V(typ)   V(min)   V(max)
0s        2.714uV    13.81uV    1.234uV
453ps     -2.077mV   10.55uV    -6.083mV
885ps     139.1mV    29.55mV    307.4mV
1.147ns   280.5mV    145.3mV    359.4mV
1.548ns   345.7mV    280.6mV    441.3mV
2.658ns   476.4mV    366.4mV    711.1mV
4.091ns   696.6mV    490.8mV    825.3mV
6.708ns   827.2mV    712.6mV    836.7mV
9.608ns   837.3mV    779.9mV    837mV
50ns      838.3mV    793.9mV    837mV
[Rising Waveform]
R_fixture= 50.000
V_fixture= 1.800
V_fixture_min= 1.750
V_fixture_max= 1.850
|time   V(typ)   V(min)   V(max)
0s        930.2mV    916.2mV    994.9mV
395ps     929.9mV    916.3mV    1.013V
509ps     968.5mV    916.6mV    1.508V
581ps     1.282V     935.4mV    1.668V
627ps     1.452V     1.006V     1.727V
689ps     1.593V     1.243V     1.777V
758ps     1.682V     1.457V     1.808V
838ps     1.738V     1.595V     1.828V
1.238ns   1.797V     1.742V     1.849V
50ns      1.8V       1.75V      1.85V
[Falling Waveform]
R_fixture= 50.000
V_fixture= 1.800
V_fixture_min= 1.750
V_fixture_max= 1.850
|time   V(typ)   V(min)   V(max)
0s        1.8V       1.75V      1.85V
1.26ns    1.801V     1.751V     1.828V
1.609ns   1.799V     1.75V      1.721V
2.175ns   1.759V     1.747V     1.449V
3.029ns   1.565V     1.702V     1.096V
4.413ns   1.165V     1.506V     1.012V
5.263ns   1.038V     1.351V     1.003V
7.011ns   960.7mV    1.086V     996.7mV
10.66ns   934.1mV    947.3mV    995mV
50ns      930.2mV    916.2mV    994.9mV
[Falling Waveform]
R_fixture= 50.000
V_fixture= 0.0
V_fixture_min= 0.0
V_fixture_max= 0.0
|time   V(typ)   V(min)   V(max)
0s        838.2mV    793.9mV    837mV
394ps     838.2mV    793.9mV    827.8mV
441ps     838.9mV    793.9mV    737.5mV
501ps     815.7mV    794.4mV    504.9mV
580ps     607.7mV    783.8mV    249mV
674ps     287mV      620.3mV    111mV
770ps     128.4mV    338.2mV    50.02mV
918ps     39.44mV    103.2mV    15.58mV
1.17ns    6.314mV    15.75mV    3.135mV
50ns      2.737uV    13.8uV     1.251uV
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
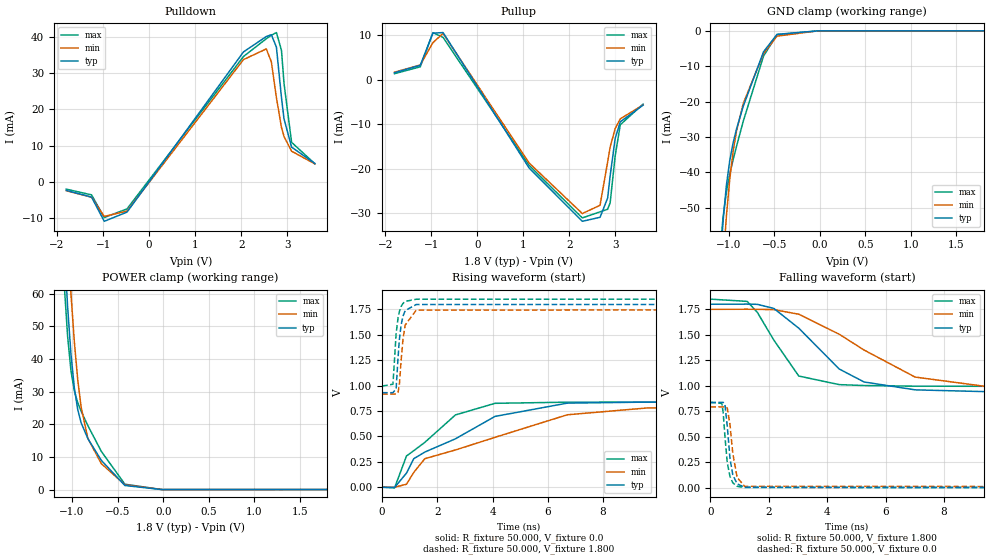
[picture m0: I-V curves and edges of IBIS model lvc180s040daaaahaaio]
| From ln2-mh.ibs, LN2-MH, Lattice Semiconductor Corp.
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|   Model lvc180s040daaaahaaio
[Model] lvc180s040daaaahaaio
| Clamp models do not include dynamic input termination. Please refer to
| the lvc180axxxdaaaahaain model for input termination.
Model_type I/O
Polarity   Non-Inverting
Enable   Active-Low
Vinl =  0.630V
Vinh =  1.170V
Vmeas =  0.900V
Cref =  0.0F
Rref =  1.000M
Vref =  0.0V
C_comp   2.000pF   1.500pF   2.500pF
[Temperature Range]   25.000   0.125k   -40.000
[Voltage Range]   1.800V   1.750V   1.850V
[C Comp Corner]
C_comp   2.000pF   1.500pF   2.500pF
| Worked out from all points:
|   slope of the pulldown table from 0 to 0.27 V, typ, clamps not added: 56 ohm
|   slope of the pullup table from 0 to 0.27 V, typ, clamps not added: 56.4 ohm
|   GND clamp passes 1 mA (typ) near -0.47 V on its own axis
|   POWER clamp passes 1 mA (typ) near -0.40 V on its own axis
|   rising waveform, R_fixture 50.000, V_fixture 0.0: 20-80 % time 2.98ns typ, 4.41ns min, 1.81ns max; typ from 0 V to 0.838 V
|   rising waveform, R_fixture 50.000, V_fixture 1.800: 20-80 % time 164ps typ, 179ps min, 156ps max; typ from 0.93 V to 1.8 V
|   falling waveform, R_fixture 50.000, V_fixture 1.800: 20-80 % time 1.91ns typ, 3.1ns min, 1.08ns max; typ from 1.8 V to 0.93 V
|   falling waveform, R_fixture 50.000, V_fixture 0.0: 20-80 % time 175ps typ, 195ps min, 164ps max; typ from 0.838 V to 0 V
[Pulldown]
|Voltage   I(typ)   I(min)   I(max)
-1.8V     -2.356mA   -2.442mA   -2.008mA
-1.25V    -4.196mA   -4.251mA   -3.59mA
-975mV    -10.89mA   -9.547mA   -9.847mA
-480mV    -8.346mA   -8.075mA   -7.463mA
2.05V     35.9mA     33.78mA    34.63mA
2.545V    40.14mA    36.72mA    39.53mA
2.655V    40.66mA    33.17mA    40.5mA
2.765V    37.24mA    23.26mA    41.24mA
2.875V    23.27mA    15.04mA    36.32mA
2.93V     17.43mA    12.54mA    27.21mA
3.095V    9.592mA    8.467mA    10.92mA
3.6V      5.086mA    4.976mA    5.008mA
[Pullup]
|Voltage   I(typ)   I(min)   I(max)
-1.8V     1.57mA     1.685mA    1.357mA
-1.24V    3.252mA    3.325mA    2.904mA
-965mV    10.47mA    8.347mA    10.59mA
-745mV    10.61mA    10.41mA    9.532mA
1.125V    -19.87mA   -18.74mA   -19.28mA
2.28V     -31.85mA   -30.11mA   -31.09mA
2.665V    -30.95mA   -28.24mA   -29.72mA
2.83V     -26.62mA   -18.51mA   -29.14mA
2.885V    -21.58mA   -15.13mA   -27.67mA
2.995V    -13.15mA   -10.94mA   -17.03mA
3.105V    -9.467mA   -8.79mA    -10.13mA
3.6V      -5.724mA   -5.679mA   -5.477mA
[GND_clamp]
|Voltage   I(typ)   I(min)   I(max)
-1.8V     -571mA     -571.9mA   -573mA
-1.097V   -67.89mA   -81.9mA    -63.82mA
-1.06V    -53.86mA   -65.72mA   -52.69mA
-1.023V   -43.6mA    -52.29mA   -45.48mA
-986mV    -36.55mA   -41.78mA   -40.47mA
-949mV    -31.59mA   -33.97mA   -36.38mA
-912mV    -27.73mA   -28.25mA   -32.63mA
-838mV    -21.28mA   -20.51mA   -25.51mA
-616mV    -5.929mA   -6.389mA   -7.151mA
-468mV    -1.006mA   -1.514mA   -1.077mA
-24mV     -25.08uA   -21.99uA   -30.46uA
1.8V      -83.5nA    0A         -36.66uA
[POWER_clamp]
|Voltage   I(typ)   I(min)   I(max)
-1.789V   617.6mA    624.8mA    616.1mA
-1.086V   74.57mA    97.6mA     62.94mA
-1.049V   56.15mA    77.62mA    47.03mA
-1.012V   41.52mA    60.02mA    36.39mA
-975mV    31.15mA    45.29mA    30.27mA
-938mV    24.56mA    33.75mA    26.65mA
-901mV    20.5mA     25.36mA    24.04mA
-827mV    15.64mA    15.72mA    19.63mA
-679mV    8.958mA    7.957mA    11.71mA
-420mV    1.258mA    1.471mA    1.65mA
-13mV     8.76uA     8.311uA    10.26uA
1.8V      0A         0A         63.06uA
[Ramp]
| variable   typ   min   max
dV/dt_r   0.503/2.986n   0.476/4.418n   0.502/1.814n
dV/dt_f   0.522/1.915n   0.500/3.122n   0.513/1.079n
R_load = 50.000
[Rising Waveform]
R_fixture= 50.000
V_fixture= 0.0
V_fixture_min= 0.0
V_fixture_max= 0.0
|time   V(typ)   V(min)   V(max)
0s        2.714uV    13.81uV    1.234uV
453ps     -2.077mV   10.55uV    -6.083mV
885ps     139.1mV    29.55mV    307.4mV
1.147ns   280.5mV    145.3mV    359.4mV
1.548ns   345.7mV    280.6mV    441.3mV
2.658ns   476.4mV    366.4mV    711.1mV
4.091ns   696.6mV    490.8mV    825.3mV
6.708ns   827.2mV    712.6mV    836.7mV
9.608ns   837.3mV    779.9mV    837mV
50ns      838.3mV    793.9mV    837mV
[Rising Waveform]
R_fixture= 50.000
V_fixture= 1.800
V_fixture_min= 1.750
V_fixture_max= 1.850
|time   V(typ)   V(min)   V(max)
0s        930.2mV    916.2mV    994.9mV
395ps     929.9mV    916.3mV    1.013V
509ps     968.5mV    916.6mV    1.508V
581ps     1.282V     935.4mV    1.668V
627ps     1.452V     1.006V     1.727V
689ps     1.593V     1.243V     1.777V
758ps     1.682V     1.457V     1.808V
838ps     1.738V     1.595V     1.828V
1.238ns   1.797V     1.742V     1.849V
50ns      1.8V       1.75V      1.85V
[Falling Waveform]
R_fixture= 50.000
V_fixture= 1.800
V_fixture_min= 1.750
V_fixture_max= 1.850
|time   V(typ)   V(min)   V(max)
0s        1.8V       1.75V      1.85V
1.26ns    1.801V     1.751V     1.828V
1.609ns   1.799V     1.75V      1.721V
2.174ns   1.759V     1.747V     1.449V
3.029ns   1.565V     1.702V     1.096V
4.413ns   1.165V     1.506V     1.012V
5.263ns   1.038V     1.351V     1.003V
7.011ns   960.7mV    1.086V     996.7mV
10.66ns   934.1mV    947.3mV    995mV
50ns      930.2mV    916.2mV    994.9mV
[Falling Waveform]
R_fixture= 50.000
V_fixture= 0.0
V_fixture_min= 0.0
V_fixture_max= 0.0
|time   V(typ)   V(min)   V(max)
0s        838.2mV    793.9mV    837mV
394ps     838.2mV    793.9mV    827.8mV
441ps     838.9mV    793.9mV    737.5mV
501ps     815.7mV    794.4mV    504.9mV
580ps     607.7mV    783.8mV    249mV
674ps     287mV      620.3mV    111mV
770ps     128.4mV    338.2mV    50.03mV
918ps     39.44mV    103.2mV    15.58mV
1.17ns    6.314mV    15.75mV    3.135mV
50ns      2.737uV    13.8uV     1.251uV
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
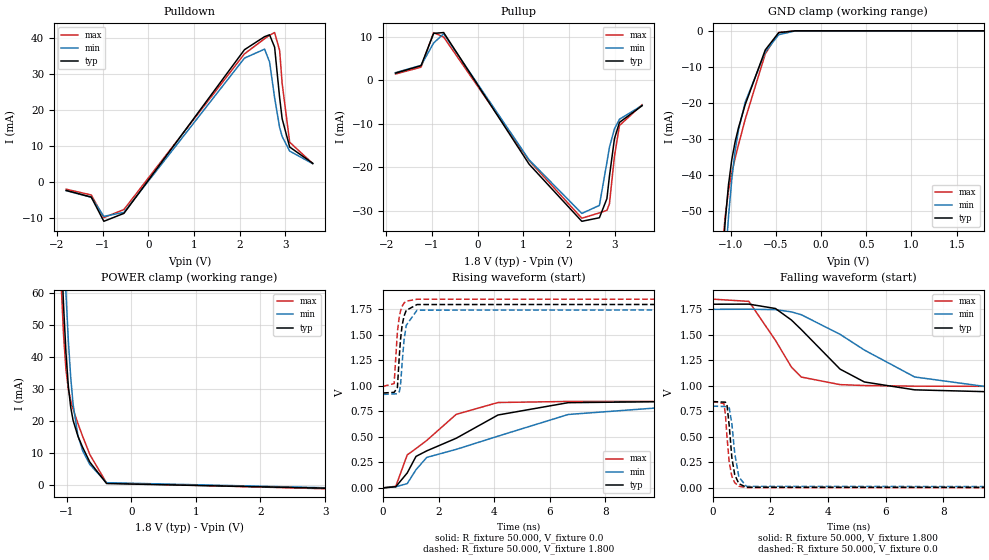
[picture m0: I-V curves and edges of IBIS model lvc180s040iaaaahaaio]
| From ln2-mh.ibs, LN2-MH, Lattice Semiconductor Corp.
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|   Model lvc180s040iaaaahaaio
[Model] lvc180s040iaaaahaaio
| Clamp models do not include dynamic input termination. Please refer to
| the lvc180axxxiaaaahaain model for input termination.
Model_type I/O
Polarity   Non-Inverting
Enable   Active-Low
Vinl =  0.630V
Vinh =  1.170V
Vmeas =  0.900V
Cref =  0.0F
Rref =  1.000M
Vref =  0.0V
C_comp   2.000pF   1.500pF   2.500pF
[Temperature Range]   25.000   0.125k   -40.000
[Voltage Range]   1.800V   1.750V   1.850V
[C Comp Corner]
C_comp   2.000pF   1.500pF   2.500pF
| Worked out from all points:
|   slope of the pulldown table from 0 to 0.27 V, typ, clamps not added: 53.9 ohm
|   slope of the pullup table from 0 to 0.27 V, typ, clamps not added: 55.3 ohm
|   GND clamp passes 1 mA (typ) near -0.50 V on its own axis
|   POWER clamp passes 1 mA (typ) near -0.41 V on its own axis
|   rising waveform, R_fixture 50.000, V_fixture 0.0: 20-80 % time 2.96ns typ, 4.38ns min, 1.8ns max; typ from 0 V to 0.846 V
|   rising waveform, R_fixture 50.000, V_fixture 1.800: 20-80 % time 159ps typ, 175ps min, 150ps max; typ from 0.93 V to 1.8 V
|   falling waveform, R_fixture 50.000, V_fixture 1.800: 20-80 % time 1.91ns typ, 3.1ns min, 1.08ns max; typ from 1.8 V to 0.93 V
|   falling waveform, R_fixture 50.000, V_fixture 0.0: 20-80 % time 176ps typ, 196ps min, 165ps max; typ from 0.846 V to 0 V
[Pulldown]
|Voltage   I(typ)   I(min)   I(max)
-1.8V     -2.429mA   -2.505mA   -2.09mA
-1.25V    -4.291mA   -4.331mA   -3.697mA
-975mV    -11.03mA   -9.654mA   -10mA
-535mV    -8.824mA   -8.548mA   -7.766mA
2.105V    36.76mA    34.42mA    35.61mA
2.545V    40.39mA    36.91mA    39.82mA
2.655V    40.91mA    33.33mA    40.79mA
2.765V    37.46mA    23.37mA    41.53mA
2.875V    23.4mA     15.11mA    36.54mA
2.93V     17.53mA    12.6mA     27.37mA
3.095V    9.655mA    8.516mA    10.99mA
3.6V      5.126mA    5.01mA     5.05mA
[Pullup]
|Voltage   I(typ)   I(min)   I(max)
-1.8V     1.616mA    1.727mA    1.404mA
-1.24V    3.334mA    3.394mA    2.991mA
-965mV    10.72mA    8.508mA    10.9mA
-745mV    10.91mA    10.64mA    9.881mA
1.125V    -19.23mA   -18.24mA   -18.42mA
2.28V     -32.33mA   -30.53mA   -31.63mA
2.665V    -31.52mA   -28.69mA   -30.4mA
2.83V     -27.13mA   -18.81mA   -29.82mA
2.885V    -22mA      -15.38mA   -28.33mA
2.995V    -13.41mA   -11.14mA   -17.44mA
3.105V    -9.66mA    -8.947mA   -10.38mA
3.6V      -5.851mA   -5.791mA   -5.625mA
[GND_clamp]
|Voltage   I(typ)   I(min)   I(max)
-1.8V     -569.8mA   -570.8mA   -571.6mA
-1.097V   -66.86mA   -81.02mA   -62.54mA
-1.06V    -52.83mA   -64.84mA   -51.42mA
-1.023V   -42.57mA   -51.42mA   -44.23mA
-986mV    -35.54mA   -40.92mA   -39.25mA
-949mV    -30.61mA   -33.13mA   -35.19mA
-912mV    -26.78mA   -27.43mA   -31.48mA
-838mV    -20.4mA    -19.75mA   -24.45mA
-616mV    -5.27mA    -5.819mA   -6.352mA
-468mV    -506.6uA   -1.081mA   -470.6uA
-283mV    -1.427uA   -17.24uA   -284.7nA
1.8V      0A         0A         0A
[POWER_clamp]
|Voltage   I(typ)   I(min)   I(max)
-1.789V   617.6mA    624.8mA    616.1mA
-1.086V   74.45mA    97.52mA    62.79mA
-1.049V   56mA       77.52mA    46.83mA
-1.012V   41.34mA    59.91mA    36.16mA
-975mV    30.94mA    45.16mA    30mA
-938mV    24.33mA    33.6mA     26.37mA
-901mV    20.25mA    25.2mA     23.75mA
-827mV    15.39mA    15.54mA    19.34mA
-753mV    11.85mA    10.81mA    15.26mA
-642mV    7.266mA    6.521mA    9.605mA
-383mV    595.8uA    860.9uA    753.9uA
3.6V      -1.113mA   -985.8uA   -1.346mA
[Ramp]
| variable   typ   min   max
dV/dt_r   0.508/2.967n   0.481/4.396n   0.508/1.802n
dV/dt_f   0.522/1.915n   0.500/3.119n   0.513/1.078n
R_load = 50.000
[Rising Waveform]
R_fixture= 50.000
V_fixture= 0.0
V_fixture_min= 0.0
V_fixture_max= 0.0
|time   V(typ)   V(min)   V(max)
0s        2.714uV    13.81uV    1.234uV
454ps     11.13mV    10.6mV     15.65mV
866ps     146.1mV    41.89mV    323mV
1.182ns   308.4mV    177.7mV    385.2mV
1.568ns   362.7mV    298.4mV    464.7mV
2.627ns   486.1mV    377.1mV    720.4mV
4.132ns   714.3mV    506.8mV    836.6mV
6.658ns   835.1mV    719.3mV    847mV
10.25ns   845.7mV    791.7mV    847.3mV
50ns      846.2mV    801.2mV    847.3mV
[Rising Waveform]
R_fixture= 50.000
V_fixture= 1.800
V_fixture_min= 1.750
V_fixture_max= 1.850
|time   V(typ)   V(min)   V(max)
0s        930.2mV    916.2mV    994.9mV
395ps     936mV      920.7mV    1.022V
513ps     983.6mV    922.6mV    1.532V
581ps     1.292V     941.5mV    1.679V
623ps     1.45V      1.002V     1.732V
678ps     1.584V     1.208V     1.778V
750ps     1.683V     1.446V     1.811V
830ps     1.74V      1.593V     1.83V
1.22ns    1.797V     1.742V     1.849V
50ns      1.8V       1.75V      1.85V
[Falling Waveform]
R_fixture= 50.000
V_fixture= 1.800
V_fixture_min= 1.750
V_fixture_max= 1.850
|time   V(typ)   V(min)   V(max)
0s        1.8V       1.75V      1.85V
1.26ns    1.801V     1.751V     1.828V
2.181ns   1.758V     1.747V     1.446V
2.735ns   1.645V     1.725V     1.184V
3.079ns   1.551V     1.697V     1.086V
4.42ns    1.164V     1.505V     1.012V
5.262ns   1.038V     1.351V     1.003V
7.005ns   960.8mV    1.087V     996.7mV
10.66ns   934.1mV    947.3mV    995mV
50ns      930.2mV    916.2mV    994.9mV
[Falling Waveform]
R_fixture= 50.000
V_fixture= 0.0
V_fixture_min= 0.0
V_fixture_max= 0.0
|time   V(typ)   V(min)   V(max)
0s        846.2mV    801.2mV    847.3mV
397ps     840.4mV    797.4mV    826.2mV
446ps     840.4mV    796.1mV    723.5mV
500ps     817.7mV    795.6mV    509.8mV
580ps     608.1mV    784.4mV    249.4mV
671ps     294.7mV    628.8mV    113.9mV
770ps     128.5mV    338.6mV    50.08mV
915ps     40.41mV    105.7mV    15.96mV
1.175ns   6.12mV     15.22mV    3.066mV
50ns      2.737uV    13.8uV     1.251uV
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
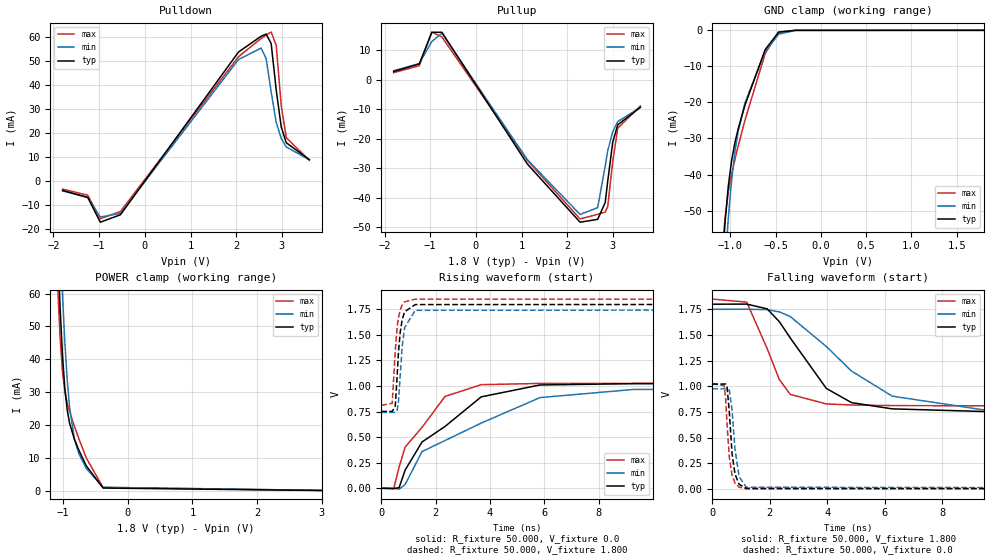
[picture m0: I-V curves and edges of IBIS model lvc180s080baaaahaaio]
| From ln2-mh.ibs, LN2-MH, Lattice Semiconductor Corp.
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|   Model lvc180s080baaaahaaio
[Model] lvc180s080baaaahaaio
| Clamp models do not include dynamic input termination. Please refer to
| the lvc180axxxbaaaahaain model for input termination.
Model_type I/O
Polarity   Non-Inverting
Enable   Active-Low
Vinl =  0.630V
Vinh =  1.170V
Vmeas =  0.900V
Cref =  0.0F
Rref =  1.000M
Vref =  0.0V
C_comp   2.000pF   1.500pF   2.500pF
[Temperature Range]   25.000   0.125k   -40.000
[Voltage Range]   1.800V   1.750V   1.850V
[C Comp Corner]
C_comp   2.000pF   1.500pF   2.500pF
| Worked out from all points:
|   slope of the pulldown table from 0 to 0.27 V, typ, clamps not added: 35.6 ohm
|   slope of the pullup table from 0 to 0.27 V, typ, clamps not added: 37.7 ohm
|   GND clamp passes 1 mA (typ) near -0.50 V on its own axis
|   POWER clamp passes 1 mA (typ) near -0.40 V on its own axis
|   rising waveform, R_fixture 50.000, V_fixture 0.0: 20-80 % time 2.36ns typ, 3.55ns min, 1.44ns max; typ from 0 V to 1.02 V
|   rising waveform, R_fixture 50.000, V_fixture 1.800: 20-80 % time 172ps typ, 184ps min, 166ps max; typ from 0.752 V to 1.8 V
|   falling waveform, R_fixture 50.000, V_fixture 1.800: 20-80 % time 1.61ns typ, 2.59ns min, 882ps max; typ from 1.8 V to 0.752 V
|   falling waveform, R_fixture 50.000, V_fixture 0.0: 20-80 % time 173ps typ, 191ps min, 161ps max; typ from 1.02 V to 0 V
[Pulldown]
|Voltage   I(typ)   I(min)   I(max)
-1.8V     -3.991mA   -4.151mA   -3.422mA
-1.25V    -6.863mA   -6.928mA   -5.945mA
-975mV    -17.17mA   -15.03mA   -15.74mA
-535mV    -14.08mA   -13.51mA   -12.74mA
2.05V     53.58mA    50.48mA    51.63mA
2.545V    60.15mA    55.23mA    59.21mA
2.655V    61.04mA    50.81mA    60.67mA
2.765V    57.11mA    36.96mA    61.87mA
2.875V    37.8mA     24.36mA    56.35mA
2.985V    22.42mA    17.66mA    31.3mA
3.095V    15.87mA    14.1mA     18.01mA
3.6V      8.838mA    8.776mA    8.549mA
[Pullup]
|Voltage   I(typ)   I(min)   I(max)
-1.8V     2.75mA     2.979mA    2.346mA
-1.24V    5.272mA    5.427mA    4.663mA
-965mV    16mA       12.87mA    16.07mA
-745mV    16.01mA    15.68mA    14.42mA
1.125V    -28.55mA   -27.09mA   -27.34mA
2.28V     -48.27mA   -45.65mA   -47.17mA
2.665V    -47.31mA   -43.36mA   -45.61mA
2.83V     -41.63mA   -29.38mA   -44.85mA
2.885V    -34.45mA   -24.17mA   -42.98mA
2.995V    -21.22mA   -17.6mA    -27.73mA
3.105V    -15.29mA   -14.21mA   -16.44mA
3.6V      -9.402mA   -9.406mA   -8.934mA
[GND_clamp]
|Voltage   I(typ)   I(min)   I(max)
-1.8V     -570.8mA   -571.7mA   -572.8mA
-1.097V   -67.45mA   -81.54mA   -63.25mA
-1.06V    -53.36mA   -65.33mA   -52.04mA
-1.023V   -43.04mA   -51.86mA   -44.77mA
-986mV    -35.95mA   -41.32mA   -39.74mA
-949mV    -30.97mA   -33.48mA   -35.64mA
-912mV    -27.1mA    -27.74mA   -31.88mA
-838mV    -20.66mA   -19.98mA   -24.78mA
-616mV    -5.345mA   -5.898mA   -6.456mA
-468mV    -515.9uA   -1.096mA   -482.9uA
-283mV    -1.482uA   -17.52uA   -322.5nA
1.8V      0A         0A         0A
[POWER_clamp]
|Voltage   I(typ)   I(min)   I(max)
-1.789V   617.6mA    624.8mA    616.1mA
-1.086V   74.57mA    97.6mA     62.94mA
-1.049V   56.15mA    77.62mA    47.03mA
-1.012V   41.52mA    60.02mA    36.39mA
-975mV    31.15mA    45.29mA    30.27mA
-938mV    24.56mA    33.75mA    26.65mA
-901mV    20.5mA     25.36mA    24.04mA
-827mV    15.64mA    15.72mA    19.63mA
-753mV    12.1mA     11mA       15.55mA
-642mV    7.512mA    6.704mA    9.896mA
-383mV    772.8uA    998.1uA    969uA
3.6V      -108.1uA   -110.5uA   -109.2uA
[Ramp]
| variable   typ   min   max
dV/dt_r   0.614/2.366n   0.586/3.556n   0.615/1.446n
dV/dt_f   0.629/1.616n   0.605/2.592n   0.623/0.884n
R_load = 50.000
[Rising Waveform]
R_fixture= 50.000
V_fixture= 0.0
V_fixture_min= 0.0
V_fixture_max= 0.0
|time   V(typ)   V(min)   V(max)
0s        2.136uV    10.9uV     979.8nV
458ps     -2.974mV   -39.51uV   -4.705mV
655ps     6.062mV    -8.886mV   207.7mV
875ps     177mV      35.96mV    402.1mV
1.497ns   452.4mV    358.6mV    595.6mV
2.345ns   604.6mV    466.9mV    898.1mV
3.675ns   893.7mV    637.4mV    1.013V
5.837ns   1.01V      886.4mV    1.025V
9.285ns   1.023V     966.3mV    1.025V
50ns      1.023V     976.3mV    1.025V
[Rising Waveform]
R_fixture= 50.000
V_fixture= 1.800
V_fixture_min= 1.750
V_fixture_max= 1.850
|time   V(typ)   V(min)   V(max)
0s        751.5mV    741.2mV    811.1mV
401ps     751mV      741.3mV    830.7mV
513ps     803.6mV    741.4mV    1.343V
581ps     1.092V     763.7mV    1.572V
632ps     1.332V     849.8mV    1.671V
694ps     1.523V     1.099V     1.744V
767ps     1.648V     1.382V     1.792V
857ps     1.726V     1.571V     1.823V
1.248ns   1.796V     1.74V      1.849V
50ns      1.8V       1.75V      1.85V
[Falling Waveform]
R_fixture= 50.000
V_fixture= 1.800
V_fixture_min= 1.750
V_fixture_max= 1.850
|time   V(typ)   V(min)   V(max)
0s        1.8V       1.75V      1.85V
1.196ns   1.801V     1.751V     1.82V
1.906ns   1.755V     1.747V     1.369V
2.332ns   1.63V      1.725V     1.067V
2.711ns   1.472V     1.68V      922.4mV
3.966ns   980.6mV    1.389V     829.6mV
4.845ns   842.3mV    1.149V     819.1mV
6.261ns   781.5mV    905.2mV    813.4mV
9.421ns   756mV      772.6mV    811.3mV
50ns      751.5mV    741.2mV    811.1mV
[Falling Waveform]
R_fixture= 50.000
V_fixture= 0.0
V_fixture_min= 0.0
V_fixture_max= 0.0
|time   V(typ)   V(min)   V(max)
0s        1.023V     976.3mV    1.025V
408ps     1.023V     976.3mV    1.008V
459ps     1.024V     976.2mV    899.2mV
514ps     991.5mV    976.8mV    619.5mV
593ps     738.9mV    961.3mV    304.1mV
685ps     347.8mV    768.4mV    137.9mV
787ps     148.1mV    389.3mV    59.21mV
932ps     46.71mV    121.2mV    19.1mV
1.181ns   7.855mV    18.98mV    4.123mV
50ns      2.162uV    10.92uV    996.6nV
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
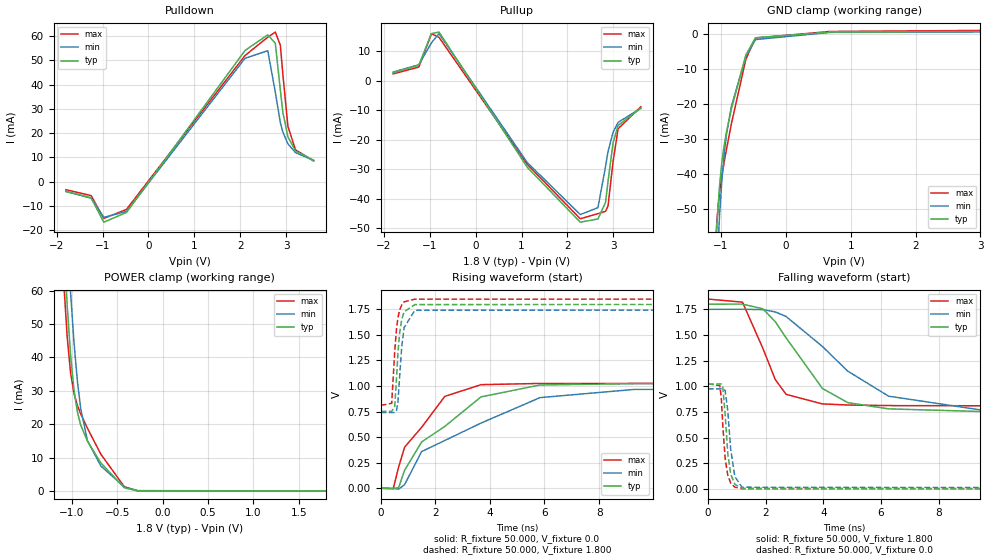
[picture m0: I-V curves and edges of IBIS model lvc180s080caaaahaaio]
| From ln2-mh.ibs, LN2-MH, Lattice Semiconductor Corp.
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|   Model lvc180s080caaaahaaio
[Model] lvc180s080caaaahaaio
| Clamp models do not include dynamic input termination. Please refer to
| the lvc180axxxcaaaahaain model for input termination.
Model_type I/O
Polarity   Non-Inverting
Enable   Active-Low
Vinl =  0.630V
Vinh =  1.170V
Vmeas =  0.900V
Cref =  0.0F
Rref =  1.000M
Vref =  0.0V
C_comp   2.000pF   1.500pF   2.500pF
[Temperature Range]   25.000   0.125k   -40.000
[Voltage Range]   1.800V   1.750V   1.850V
[C Comp Corner]
C_comp   2.000pF   1.500pF   2.500pF
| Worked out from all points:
|   slope of the pulldown table from 0 to 0.27 V, typ, clamps not added: 37 ohm
|   slope of the pullup table from 0 to 0.27 V, typ, clamps not added: 37.2 ohm
|   GND clamp passes 1 mA (typ) near -0.47 V on its own axis
|   POWER clamp passes 1 mA (typ) near -0.42 V on its own axis
|   rising waveform, R_fixture 50.000, V_fixture 0.0: 20-80 % time 2.36ns typ, 3.55ns min, 1.44ns max; typ from 0 V to 1.02 V
|   rising waveform, R_fixture 50.000, V_fixture 1.800: 20-80 % time 172ps typ, 184ps min, 166ps max; typ from 0.752 V to 1.8 V
|   falling waveform, R_fixture 50.000, V_fixture 1.800: 20-80 % time 1.61ns typ, 2.59ns min, 882ps max; typ from 1.8 V to 0.752 V
|   falling waveform, R_fixture 50.000, V_fixture 0.0: 20-80 % time 173ps typ, 191ps min, 161ps max; typ from 1.02 V to 0 V
[Pulldown]
|Voltage   I(typ)   I(min)   I(max)
-1.8V     -3.869mA   -4.043mA   -3.282mA
-1.25V    -6.664mA   -6.758mA   -5.713mA
-975mV    -16.67mA   -14.67mA   -15.11mA
-480mV    -12.67mA   -12.24mA   -11.42mA
2.105V    54.1mA     50.87mA    52.02mA
2.6V      60.56mA    54.03mA    59.58mA
2.765V    57.09mA    36.96mA    61.68mA
2.875V    37.8mA     24.36mA    56.27mA
2.93V     28.57mA    20.45mA    44.26mA
3.04V     18.51mA    15.62mA    22.83mA
3.205V    12.78mA    12.03mA    13.17mA
3.6V      8.849mA    8.783mA    8.552mA
[Pullup]
|Voltage   I(typ)   I(min)   I(max)
-1.8V     2.76mA     2.986mA    2.349mA
-1.24V    5.283mA    5.432mA    4.658mA
-965mV    15.98mA    12.86mA    15.93mA
-800mV    16.5mA     15.98mA    14.73mA
1.125V    -29.29mA   -27.69mA   -28.3mA
2.28V     -47.88mA   -45.3mA    -46.73mA
2.665V    -46.79mA   -42.96mA   -44.98mA
2.83V     -41.19mA   -29.11mA   -44.22mA
2.885V    -34.1mA    -23.95mA   -42.39mA
2.995V    -20.99mA   -17.43mA   -27.37mA
3.105V    -15.11mA   -14.06mA   -16.22mA
3.6V      -9.28mA    -9.3mA     -8.792mA
[GND_clamp]
|Voltage   I(typ)   I(min)   I(max)
-1.8V     -571mA     -571.9mA   -573mA
-1.097V   -67.89mA   -81.9mA    -63.82mA
-1.06V    -53.86mA   -65.72mA   -52.69mA
-1.023V   -43.6mA    -52.29mA   -45.48mA
-986mV    -36.55mA   -41.78mA   -40.47mA
-949mV    -31.59mA   -33.97mA   -36.38mA
-912mV    -27.73mA   -28.25mA   -32.63mA
-838mV    -21.28mA   -20.51mA   -25.51mA
-616mV    -5.929mA   -6.39mA    -7.151mA
-468mV    -1.006mA   -1.514mA   -1.077mA
679mV     636.6uA    525.1uA    801uA
3.6V      859.5uA    698.9uA    1.171mA
[POWER_clamp]
|Voltage   I(typ)   I(min)   I(max)
-1.789V   616.8mA    624.1mA    614.9mA
-1.086V   73.72mA    96.92mA    61.82mA
-1.049V   55.3mA     76.94mA    45.93mA
-1.012V   40.68mA    59.35mA    35.33mA
-975mV    30.32mA    44.62mA    29.25mA
-938mV    23.76mA    33.09mA    25.68mA
-901mV    19.73mA    24.71mA    23.1mA
-827mV    14.94mA    15.12mA    18.78mA
-679mV    8.384mA    7.465mA    11.01mA
-420mV    917.4uA    1.181mA    1.232mA
-272mV    19.37uA    92.48uA    11.5uA
1.8V      0A         0A         0A
[Ramp]
| variable   typ   min   max
dV/dt_r   0.614/2.366n   0.586/3.556n   0.615/1.446n
dV/dt_f   0.629/1.616n   0.605/2.593n   0.623/0.884n
R_load = 50.000
[Rising Waveform]
R_fixture= 50.000
V_fixture= 0.0
V_fixture_min= 0.0
V_fixture_max= 0.0
|time   V(typ)   V(min)   V(max)
0s        2.136uV    10.9uV     979.8nV
458ps     -2.974mV   -39.51uV   -4.705mV
655ps     6.062mV    -8.886mV   207.7mV
875ps     177mV      35.96mV    402.1mV
1.497ns   452.4mV    358.6mV    595.6mV
2.345ns   604.6mV    466.9mV    898.1mV
3.675ns   893.7mV    637.4mV    1.013V
5.837ns   1.01V      886.4mV    1.025V
9.285ns   1.023V     966.3mV    1.025V
50ns      1.023V     976.3mV    1.025V
[Rising Waveform]
R_fixture= 50.000
V_fixture= 1.800
V_fixture_min= 1.750
V_fixture_max= 1.850
|time   V(typ)   V(min)   V(max)
0s        751.5mV    741.2mV    811.1mV
401ps     751mV      741.3mV    830.7mV
513ps     803.6mV    741.4mV    1.343V
581ps     1.092V     763.7mV    1.572V
632ps     1.332V     849.8mV    1.671V
694ps     1.523V     1.099V     1.744V
767ps     1.648V     1.382V     1.792V
857ps     1.726V     1.571V     1.823V
1.248ns   1.796V     1.74V      1.849V
50ns      1.8V       1.75V      1.85V
[Falling Waveform]
R_fixture= 50.000
V_fixture= 1.800
V_fixture_min= 1.750
V_fixture_max= 1.850
|time   V(typ)   V(min)   V(max)
0s        1.8V       1.75V      1.85V
1.196ns   1.801V     1.751V     1.82V
1.906ns   1.755V     1.747V     1.369V
2.332ns   1.63V      1.725V     1.067V
2.711ns   1.472V     1.68V      922.4mV
3.966ns   980.6mV    1.389V     829.6mV
4.845ns   842.3mV    1.149V     819.1mV
6.261ns   781.5mV    905.2mV    813.4mV
9.421ns   756mV      772.6mV    811.3mV
50ns      751.5mV    741.2mV    811.1mV
[Falling Waveform]
R_fixture= 50.000
V_fixture= 0.0
V_fixture_min= 0.0
V_fixture_max= 0.0
|time   V(typ)   V(min)   V(max)
0s        1.023V     976.3mV    1.025V
408ps     1.023V     976.3mV    1.008V
459ps     1.024V     976.2mV    899.2mV
514ps     991.5mV    976.8mV    619.5mV
593ps     738.9mV    961.3mV    304.1mV
685ps     347.8mV    768.4mV    137.9mV
787ps     148.1mV    389.3mV    59.21mV
932ps     46.71mV    121.2mV    19.1mV
1.181ns   7.855mV    18.98mV    4.123mV
50ns      2.162uV    10.92uV    996.6nV
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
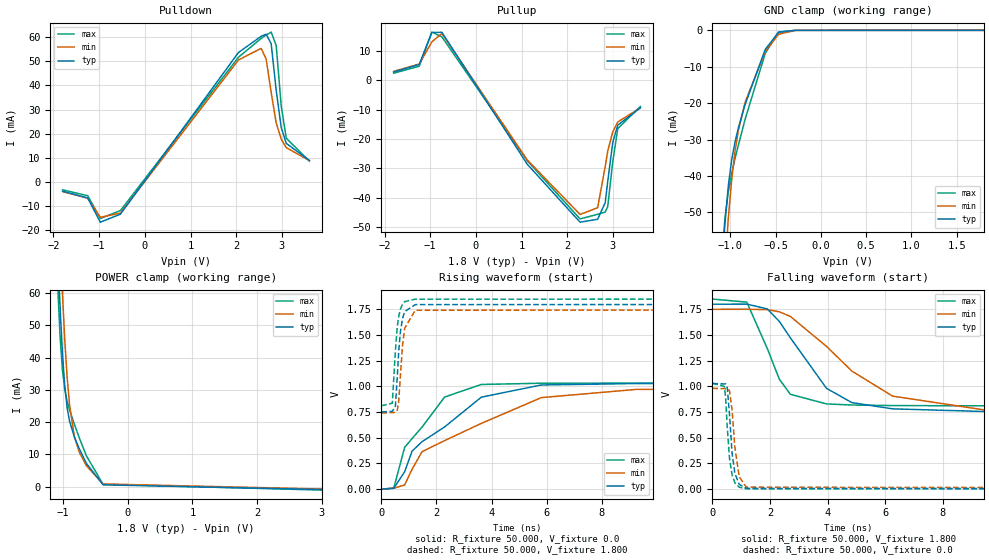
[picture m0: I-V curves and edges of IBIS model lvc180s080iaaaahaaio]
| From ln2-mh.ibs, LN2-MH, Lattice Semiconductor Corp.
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|   Model lvc180s080iaaaahaaio
[Model] lvc180s080iaaaahaaio
| Clamp models do not include dynamic input termination. Please refer to
| the lvc180axxxiaaaahaain model for input termination.
Model_type I/O
Polarity   Non-Inverting
Enable   Active-Low
Vinl =  0.630V
Vinh =  1.170V
Vmeas =  0.900V
Cref =  0.0F
Rref =  1.000M
Vref =  0.0V
C_comp   2.000pF   1.500pF   2.500pF
[Temperature Range]   25.000   0.125k   -40.000
[Voltage Range]   1.800V   1.750V   1.850V
[C Comp Corner]
C_comp   2.000pF   1.500pF   2.500pF
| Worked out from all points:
|   slope of the pulldown table from 0 to 0.27 V, typ, clamps not added: 36 ohm
|   slope of the pullup table from 0 to 0.27 V, typ, clamps not added: 37.2 ohm
|   GND clamp passes 1 mA (typ) near -0.50 V on its own axis
|   POWER clamp passes 1 mA (typ) near -0.41 V on its own axis
|   rising waveform, R_fixture 50.000, V_fixture 0.0: 20-80 % time 2.35ns typ, 3.54ns min, 1.44ns max; typ from 0 V to 1.03 V
|   rising waveform, R_fixture 50.000, V_fixture 1.800: 20-80 % time 167ps typ, 180ps min, 162ps max; typ from 0.752 V to 1.8 V
|   falling waveform, R_fixture 50.000, V_fixture 1.800: 20-80 % time 1.61ns typ, 2.59ns min, 882ps max; typ from 1.8 V to 0.752 V
|   falling waveform, R_fixture 50.000, V_fixture 0.0: 20-80 % time 173ps typ, 191ps min, 162ps max; typ from 1.03 V to 0 V
[Pulldown]
|Voltage   I(typ)   I(min)   I(max)
-1.8V     -3.942mA   -4.106mA   -3.364mA
-1.25V    -6.76mA    -6.838mA   -5.82mA
-975mV    -16.81mA   -14.78mA   -15.27mA
-535mV    -13.49mA   -13.03mA   -12mA
2.05V     53.69mA    50.59mA    51.73mA
2.545V    60.4mA     55.41mA    59.5mA
2.655V    61.28mA    50.97mA    60.96mA
2.765V    57.32mA    37.07mA    62.16mA
2.875V    37.92mA    24.43mA    56.57mA
2.985V    22.5mA     17.72mA    31.41mA
3.095V    15.93mA    14.15mA    18.09mA
3.6V      8.878mA    8.81mA     8.591mA
[Pullup]
|Voltage   I(typ)   I(min)   I(max)
-1.8V     2.796mA    3.021mA    2.393mA
-1.24V    5.354mA    5.497mA    4.75mA
-965mV    16.25mA    13.03mA    16.38mA
-745mV    16.31mA    15.91mA    14.77mA
1.125V    -28.64mA   -27.18mA   -27.43mA
2.28V     -48.36mA   -45.73mA   -47.25mA
2.665V    -47.37mA   -43.43mA   -45.67mA
2.83V     -41.71mA   -29.44mA   -44.92mA
2.885V    -34.54mA   -24.21mA   -43.07mA
2.995V    -21.26mA   -17.63mA   -27.82mA
3.105V    -15.31mA   -14.22mA   -16.48mA
3.6V      -9.408mA   -9.413mA   -8.941mA
[GND_clamp]
|Voltage   I(typ)   I(min)   I(max)
-1.8V     -569.8mA   -570.8mA   -571.6mA
-1.097V   -66.86mA   -81.02mA   -62.54mA
-1.06V    -52.83mA   -64.84mA   -51.42mA
-1.023V   -42.57mA   -51.42mA   -44.23mA
-986mV    -35.54mA   -40.92mA   -39.25mA
-949mV    -30.61mA   -33.13mA   -35.19mA
-912mV    -26.78mA   -27.43mA   -31.48mA
-838mV    -20.4mA    -19.75mA   -24.45mA
-616mV    -5.27mA    -5.819mA   -6.352mA
-468mV    -506.6uA   -1.081mA   -470.6uA
-283mV    -1.427uA   -17.24uA   -284.7nA
1.8V      0A         0A         0A
[POWER_clamp]
|Voltage   I(typ)   I(min)   I(max)
-1.789V   617.6mA    624.8mA    616.1mA
-1.086V   74.45mA    97.52mA    62.79mA
-1.049V   56mA       77.52mA    46.83mA
-1.012V   41.34mA    59.91mA    36.16mA
-975mV    30.94mA    45.16mA    30mA
-938mV    24.33mA    33.6mA     26.37mA
-901mV    20.25mA    25.2mA     23.75mA
-827mV    15.39mA    15.54mA    19.34mA
-753mV    11.85mA    10.81mA    15.26mA
-642mV    7.266mA    6.521mA    9.605mA
-383mV    595.8uA    860.9uA    753.9uA
3.6V      -1.113mA   -985.8uA   -1.346mA
[Ramp]
| variable   typ   min   max
dV/dt_r   0.617/2.355n   0.589/3.541n   0.619/1.439n
dV/dt_f   0.629/1.614n   0.605/2.594n   0.623/0.885n
R_load = 50.000
[Rising Waveform]
R_fixture= 50.000
V_fixture= 0.0
V_fixture_min= 0.0
V_fixture_max= 0.0
|time   V(typ)   V(min)   V(max)
0s        2.136uV    10.9uV     979.8nV
452ps     8.252mV    8.864mV    10.96mV
848ps     170.3mV    41.02mV    407.5mV
1.115ns   369.7mV    193.3mV    492.2mV
1.477ns   461.9mV    364.8mV    603.7mV
2.295ns   605.2mV    472.4mV    896.4mV
3.629ns   895.3mV    640.1mV    1.019V
5.805ns   1.014V     890.9mV    1.031V
9.257ns   1.028V     971mV      1.032V
50ns      1.028V     980.9mV    1.032V
[Rising Waveform]
R_fixture= 50.000
V_fixture= 1.800
V_fixture_min= 1.750
V_fixture_max= 1.850
|time   V(typ)   V(min)   V(max)
0s        751.5mV    741.2mV    811.1mV
399ps     757.2mV    745.9mV    836.8mV
512ps     809.2mV    747mV      1.352V
581ps     1.102V     769.8mV    1.586V
632ps     1.344V     857.1mV    1.683V
693ps     1.533V     1.104V     1.752V
768ps     1.659V     1.396V     1.799V
847ps     1.728V     1.566V     1.825V
1.231ns   1.796V     1.741V     1.849V
50ns      1.8V       1.75V      1.85V
[Falling Waveform]
R_fixture= 50.000
V_fixture= 1.800
V_fixture_min= 1.750
V_fixture_max= 1.850
|time   V(typ)   V(min)   V(max)
0s        1.8V       1.75V      1.85V
1.196ns   1.801V     1.751V     1.82V
1.908ns   1.754V     1.747V     1.368V
2.327ns   1.632V     1.726V     1.07V
2.709ns   1.473V     1.681V     923mV
3.965ns   980.8mV    1.389V     829.6mV
4.845ns   842.3mV    1.149V     819.1mV
6.258ns   781.6mV    905.5mV    813.4mV
9.409ns   756.1mV    772.8mV    811.3mV
50ns      751.5mV    741.2mV    811.1mV
[Falling Waveform]
R_fixture= 50.000
V_fixture= 0.0
V_fixture_min= 0.0
V_fixture_max= 0.0
|time   V(typ)   V(min)   V(max)
0s        1.028V     980.9mV    1.032V
415ps     1.024V     977.9mV    999.5mV
459ps     1.025V     977.3mV    899.4mV
517ps     986.9mV    977.4mV    603.1mV
594ps     734.3mV    960.7mV    301.5mV
685ps     347.8mV    768.5mV    138mV
780ps     156.9mV    411.7mV    62.69mV
931ps     47.54mV    122.2mV    19.24mV
1.178ns   8.107mV    19.39mV    4.185mV
50ns      2.162uV    10.92uV    996.6nV
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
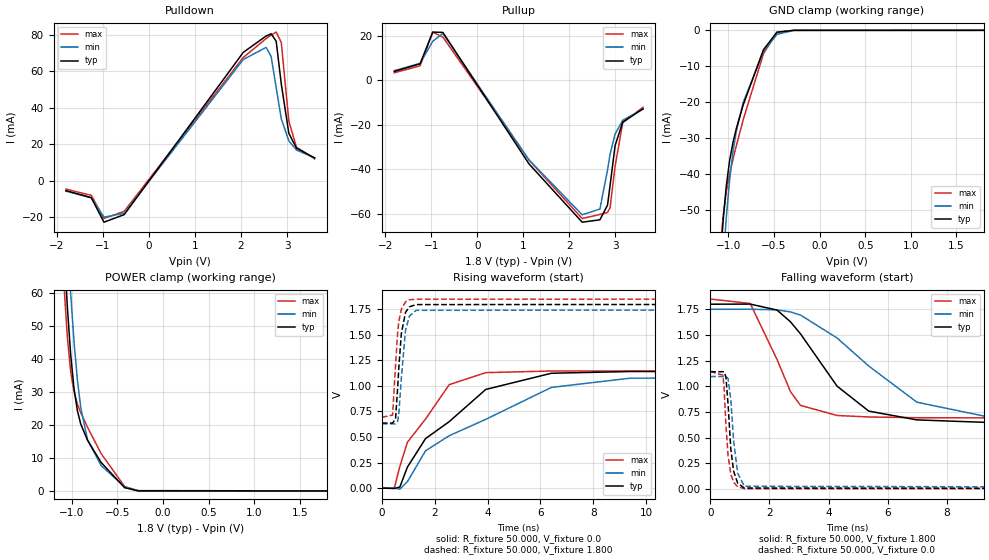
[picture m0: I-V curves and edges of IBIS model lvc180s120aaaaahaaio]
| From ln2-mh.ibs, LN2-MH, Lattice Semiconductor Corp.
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|   Model lvc180s120aaaaahaaio
[Model] lvc180s120aaaaahaaio
| Clamp models do not include dynamic input termination. Please refer to
| the lvc180axxxaaaaahaain model for input termination.
Model_type I/O
Polarity   Non-Inverting
Enable   Active-Low
Vinl =  0.630V
Vinh =  1.170V
Vmeas =  0.900V
Cref =  0.0F
Rref =  1.000M
Vref =  0.0V
C_comp   2.000pF   1.500pF   2.500pF
[Temperature Range]   25.000   0.125k   -40.000
[Voltage Range]   1.800V   1.750V   1.850V
[C Comp Corner]
C_comp   2.000pF   1.500pF   2.500pF
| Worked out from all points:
|   slope of the pulldown table from 0 to 0.27 V, typ, clamps not added: 27.2 ohm
|   slope of the pullup table from 0 to 0.27 V, typ, clamps not added: 28.4 ohm
|   GND clamp passes 1 mA (typ) near -0.49 V on its own axis
|   POWER clamp passes 1 mA (typ) near -0.42 V on its own axis
|   rising waveform, R_fixture 50.000, V_fixture 0.0: 20-80 % time 2.7ns typ, 4.08ns min, 1.59ns max; typ from 0 V to 1.14 V
|   rising waveform, R_fixture 50.000, V_fixture 1.800: 20-80 % time 192ps typ, 206ps min, 176ps max; typ from 0.637 V to 1.8 V
|   falling waveform, R_fixture 50.000, V_fixture 1.800: 20-80 % time 1.83ns typ, 2.9ns min, 1ns max; typ from 1.8 V to 0.637 V
|   falling waveform, R_fixture 50.000, V_fixture 0.0: 20-80 % time 173ps typ, 191ps min, 161ps max; typ from 1.14 V to 0 V
[Pulldown]
|Voltage   I(typ)   I(min)   I(max)
-1.8V     -5.444mA   -5.69mA    -4.62mA
-1.25V    -9.268mA   -9.362mA   -7.974mA
-975mV    -22.72mA   -19.99mA   -20.69mA
-535mV    -18.56mA   -17.81mA   -16.75mA
2.05V     70.36mA    66.44mA    67.56mA
2.545V    79.3mA     73.08mA    77.91mA
2.655V    80.56mA    68.13mA    79.84mA
2.765V    76.46mA    51.04mA    81.48mA
2.875V    53.11mA    33.98mA    75.82mA
3.04V     25.98mA    21.82mA    32.57mA
3.205V    17.87mA    16.88mA    18.41mA
3.6V      12.49mA    12.49mA    11.98mA
[Pullup]
|Voltage   I(typ)   I(min)   I(max)
-1.8V     3.926mA    4.274mA    3.323mA
-1.24V    7.345mA    7.543mA    6.433mA
-965mV    21.59mA    17.47mA    21.54mA
-745mV    21.44mA    20.98mA    19.34mA
1.125V    -37.6mA    -35.79mA   -35.89mA
2.28V     -63.77mA   -60.44mA   -62.13mA
2.665V    -62.7mA    -57.88mA   -60.29mA
2.83V     -56.13mA   -40.31mA   -59.39mA
2.885V    -47.33mA   -33.31mA   -57.3mA
2.995V    -29.37mA   -24.18mA   -38.6mA
3.16V     -18.79mA   -18.02mA   -19.16mA
3.6V      -12.88mA   -12.97mA   -12.14mA
[GND_clamp]
|Voltage   I(typ)   I(min)   I(max)
-1.8V     -570.9mA   -571.8mA   -572.9mA
-1.097V   -67.54mA   -81.64mA   -63.35mA
-1.06V    -53.45mA   -65.42mA   -52.13mA
-1.023V   -43.13mA   -51.95mA   -44.86mA
-986mV    -36.04mA   -41.41mA   -39.83mA
-949mV    -31.06mA   -33.56mA   -35.72mA
-912mV    -27.18mA   -27.83mA   -31.97mA
-838mV    -20.73mA   -20.06mA   -24.86mA
-616mV    -5.403mA   -5.958mA   -6.517mA
-468mV    -530.3uA   -1.122mA   -495.6uA
-283mV    -1.808uA   -19.61uA   -457.7nA
1.8V      0A         0A         0A
[POWER_clamp]
|Voltage   I(typ)   I(min)   I(max)
-1.789V   617.6mA    624.8mA    616.1mA
-1.086V   74.43mA    97.5mA     62.76mA
-1.049V   55.98mA    77.5mA     46.8mA
-1.012V   41.32mA    59.89mA    36.12mA
-975mV    30.91mA    45.13mA    29.96mA
-938mV    24.29mA    33.57mA    26.33mA
-901mV    20.21mA    25.16mA    23.7mA
-827mV    15.35mA    15.5mA     19.29mA
-679mV    8.657mA    7.724mA    11.36mA
-420mV    977.9uA    1.256mA    1.313mA
-272mV    22.92uA    106.7uA    14.08uA
1.8V      0A         0A         0A
[Ramp]
| variable   typ   min   max
dV/dt_r   0.686/2.705n   0.657/4.085n   0.688/1.588n
dV/dt_f   0.698/1.832n   0.673/2.907n   0.694/1.007n
R_load = 50.000
[Rising Waveform]
R_fixture= 50.000
V_fixture= 0.0
V_fixture_min= 0.0
V_fixture_max= 0.0
|time   V(typ)   V(min)   V(max)
0s        1.76uV     9.003uV    814.4nV
469ps     -3.923mV   -259.5uV   -2.248mV
681ps     10.55mV    -10.51mV   211.8mV
967ps     205.6mV    62.73mV    448.9mV
1.652ns   484.3mV    364.9mV    675.6mV
2.548ns   650.2mV    512.5mV    1.012V
3.931ns   965.4mV    672.7mV    1.13V
6.416ns   1.124V     985.4mV    1.146V
9.409ns   1.141V     1.076V     1.146V
50ns      1.143V     1.096V     1.146V
[Rising Waveform]
R_fixture= 50.000
V_fixture= 1.800
V_fixture_min= 1.750
V_fixture_max= 1.850
|time   V(typ)   V(min)   V(max)
0s        636.5mV    628.2mV    692.9mV
406ps     635.9mV    628.3mV    714.1mV
518ps     678.4mV    628.4mV    1.201V
597ps     979.6mV    652.8mV    1.522V
645ps     1.189V     740.6mV    1.633V
736ps     1.509V     1.074V     1.749V
895ps     1.72V      1.544V     1.823V
1.042ns   1.774V     1.683V     1.843V
1.294ns   1.796V     1.74V      1.849V
50ns      1.8V       1.75V      1.85V
[Falling Waveform]
R_fixture= 50.000
V_fixture= 1.800
V_fixture_min= 1.750
V_fixture_max= 1.850
|time   V(typ)   V(min)   V(max)
0s        1.8V       1.75V      1.85V
1.351ns   1.801V     1.751V     1.807V
2.256ns   1.743V     1.745V     1.263V
2.711ns   1.629V     1.725V     949.2mV
3.051ns   1.511V     1.694V     815.1mV
4.287ns   1.002V     1.471V     717mV
5.356ns   759.6mV    1.198V     702.5mV
6.982ns   674.1mV    846.1mV    695.6mV
9.79ns    645mV      679.5mV    693.3mV
50ns      636.5mV    628.2mV    692.9mV
[Falling Waveform]
R_fixture= 50.000
V_fixture= 0.0
V_fixture_min= 0.0
V_fixture_max= 0.0
|time   V(typ)   V(min)   V(max)
0s        1.143V     1.096V     1.146V
429ps     1.143V     1.096V     1.109V
467ps     1.143V     1.096V     1V
531ps     1.093V     1.097V     627mV
604ps     824.7mV    1.075V     325.3mV
695ps     394mV      876mV      148.5mV
792ps     173.6mV    469.1mV    66.69mV
928ps     58.54mV    155.8mV    22.88mV
1.155ns   11.03mV    28.12mV    5.305mV
50ns      1.787uV    9.047uV    829.5nV
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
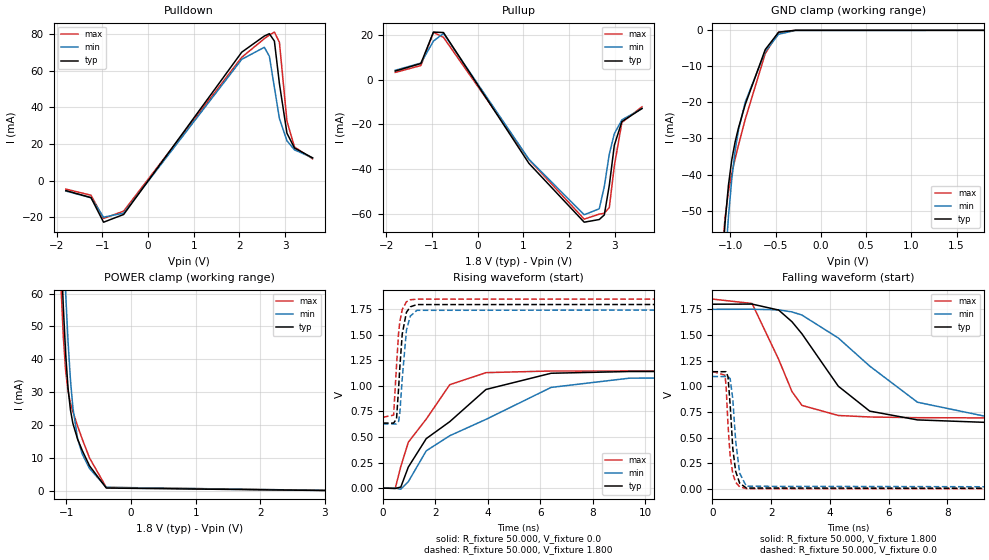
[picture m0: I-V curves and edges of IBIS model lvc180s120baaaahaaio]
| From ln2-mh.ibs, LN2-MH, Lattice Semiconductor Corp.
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|   Model lvc180s120baaaahaaio
[Model] lvc180s120baaaahaaio
| Clamp models do not include dynamic input termination. Please refer to
| the lvc180axxxbaaaahaain model for input termination.
Model_type I/O
Polarity   Non-Inverting
Enable   Active-Low
Vinl =  0.630V
Vinh =  1.170V
Vmeas =  0.900V
Cref =  0.0F
Rref =  1.000M
Vref =  0.0V
C_comp   2.000pF   1.500pF   2.500pF
[Temperature Range]   25.000   0.125k   -40.000
[Voltage Range]   1.800V   1.750V   1.850V
[C Comp Corner]
C_comp   2.000pF   1.500pF   2.500pF
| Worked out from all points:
|   slope of the pulldown table from 0 to 0.27 V, typ, clamps not added: 27.2 ohm
|   slope of the pullup table from 0 to 0.27 V, typ, clamps not added: 28.7 ohm
|   GND clamp passes 1 mA (typ) near -0.50 V on its own axis
|   POWER clamp passes 1 mA (typ) near -0.40 V on its own axis
|   rising waveform, R_fixture 50.000, V_fixture 0.0: 20-80 % time 2.7ns typ, 4.08ns min, 1.59ns max; typ from 0 V to 1.14 V
|   rising waveform, R_fixture 50.000, V_fixture 1.800: 20-80 % time 192ps typ, 206ps min, 176ps max; typ from 0.637 V to 1.8 V
|   falling waveform, R_fixture 50.000, V_fixture 1.800: 20-80 % time 1.83ns typ, 2.9ns min, 1ns max; typ from 1.8 V to 0.637 V
|   falling waveform, R_fixture 50.000, V_fixture 0.0: 20-80 % time 173ps typ, 191ps min, 161ps max; typ from 1.14 V to 0 V
[Pulldown]
|Voltage   I(typ)   I(min)   I(max)
-1.8V     -5.44mA    -5.685mA   -4.615mA
-1.25V    -9.261mA   -9.353mA   -7.967mA
-975mV    -22.7mA    -19.97mA   -20.66mA
-535mV    -18.49mA   -17.75mA   -16.67mA
2.05V     70.17mA    66.26mA    67.38mA
2.545V    79mA       72.85mA    77.56mA
2.655V    80.27mA    67.94mA    79.5mA
2.765V    76.22mA    50.91mA    81.15mA
2.875V    52.96mA    33.88mA    75.56mA
3.04V     25.9mA     21.76mA    32.47mA
3.205V    17.81mA    16.83mA    18.34mA
3.6V      12.44mA    12.45mA    11.93mA
[Pullup]
|Voltage   I(typ)   I(min)   I(max)
-1.8V     3.88mA     4.232mA    3.276mA
-1.24V    7.264mA    7.474mA    6.347mA
-965mV    21.35mA    17.32mA    21.22mA
-745mV    21.14mA    20.75mA    18.99mA
1.125V    -37.49mA   -35.68mA   -35.79mA
2.335V    -63.87mA   -60.54mA   -62.49mA
2.665V    -62.67mA   -57.85mA   -60.26mA
2.775V    -60.62mA   -47.94mA   -59.89mA
2.885V    -47.32mA   -33.29mA   -57.28mA
2.995V    -29.36mA   -24.17mA   -38.59mA
3.16V     -18.79mA   -18.01mA   -19.16mA
3.6V      -12.88mA   -12.97mA   -12.14mA
[GND_clamp]
|Voltage   I(typ)   I(min)   I(max)
-1.8V     -570.8mA   -571.7mA   -572.8mA
-1.097V   -67.45mA   -81.54mA   -63.25mA
-1.06V    -53.36mA   -65.33mA   -52.04mA
-1.023V   -43.04mA   -51.86mA   -44.77mA
-986mV    -35.95mA   -41.32mA   -39.74mA
-949mV    -30.97mA   -33.48mA   -35.64mA
-912mV    -27.1mA    -27.74mA   -31.88mA
-838mV    -20.66mA   -19.98mA   -24.78mA
-616mV    -5.345mA   -5.898mA   -6.456mA
-468mV    -515.9uA   -1.096mA   -482.9uA
-283mV    -1.482uA   -17.52uA   -322.5nA
1.8V      0A         0A         0A
[POWER_clamp]
|Voltage   I(typ)   I(min)   I(max)
-1.789V   617.6mA    624.8mA    616.1mA
-1.086V   74.57mA    97.6mA     62.94mA
-1.049V   56.15mA    77.62mA    47.03mA
-1.012V   41.52mA    60.02mA    36.39mA
-975mV    31.15mA    45.29mA    30.27mA
-938mV    24.56mA    33.75mA    26.65mA
-901mV    20.5mA     25.36mA    24.04mA
-827mV    15.64mA    15.73mA    19.63mA
-753mV    12.1mA     11mA       15.55mA
-642mV    7.512mA    6.704mA    9.896mA
-383mV    772.8uA    998.1uA    969uA
3.6V      -108.1uA   -110.5uA   -109.2uA
[Ramp]
| variable   typ   min   max
dV/dt_r   0.686/2.705n   0.657/4.085n   0.688/1.588n
dV/dt_f   0.698/1.832n   0.673/2.907n   0.694/1.007n
R_load = 50.000
[Rising Waveform]
R_fixture= 50.000
V_fixture= 0.0
V_fixture_min= 0.0
V_fixture_max= 0.0
|time   V(typ)   V(min)   V(max)
0s        1.76uV     9.003uV    814.4nV
469ps     -3.923mV   -259.5uV   -2.248mV
681ps     10.55mV    -10.51mV   211.8mV
967ps     205.6mV    62.73mV    448.9mV
1.652ns   484.3mV    364.9mV    675.6mV
2.548ns   650.2mV    512.5mV    1.012V
3.931ns   965.4mV    672.7mV    1.13V
6.416ns   1.124V     985.4mV    1.146V
9.412ns   1.141V     1.076V     1.146V
50ns      1.143V     1.096V     1.146V
[Rising Waveform]
R_fixture= 50.000
V_fixture= 1.800
V_fixture_min= 1.750
V_fixture_max= 1.850
|time   V(typ)   V(min)   V(max)
0s        636.5mV    628.2mV    692.9mV
406ps     635.9mV    628.3mV    714.1mV
518ps     678.4mV    628.4mV    1.201V
597ps     979.6mV    652.8mV    1.522V
645ps     1.189V     740.6mV    1.633V
736ps     1.509V     1.074V     1.749V
895ps     1.72V      1.544V     1.823V
1.042ns   1.774V     1.683V     1.843V
1.294ns   1.796V     1.74V      1.849V
50ns      1.8V       1.75V      1.85V
[Falling Waveform]
R_fixture= 50.000
V_fixture= 1.800
V_fixture_min= 1.750
V_fixture_max= 1.850
|time   V(typ)   V(min)   V(max)
0s        1.8V       1.75V      1.85V
1.351ns   1.801V     1.751V     1.807V
2.256ns   1.743V     1.745V     1.263V
2.711ns   1.629V     1.725V     949.2mV
3.051ns   1.511V     1.694V     815.1mV
4.287ns   1.002V     1.471V     717mV
5.356ns   759.6mV    1.198V     702.5mV
6.982ns   674.1mV    846.1mV    695.6mV
9.79ns    645mV      679.5mV    693.3mV
50ns      636.5mV    628.2mV    692.9mV
[Falling Waveform]
R_fixture= 50.000
V_fixture= 0.0
V_fixture_min= 0.0
V_fixture_max= 0.0
|time   V(typ)   V(min)   V(max)
0s        1.143V     1.096V     1.146V
429ps     1.143V     1.096V     1.109V
467ps     1.143V     1.096V     1V
531ps     1.093V     1.097V     627mV
604ps     824.7mV    1.075V     325.3mV
695ps     394mV      876mV      148.5mV
792ps     173.6mV    469.1mV    66.69mV
928ps     58.54mV    155.8mV    22.88mV
1.155ns   11.03mV    28.12mV    5.305mV
50ns      1.787uV    9.047uV    829.5nV
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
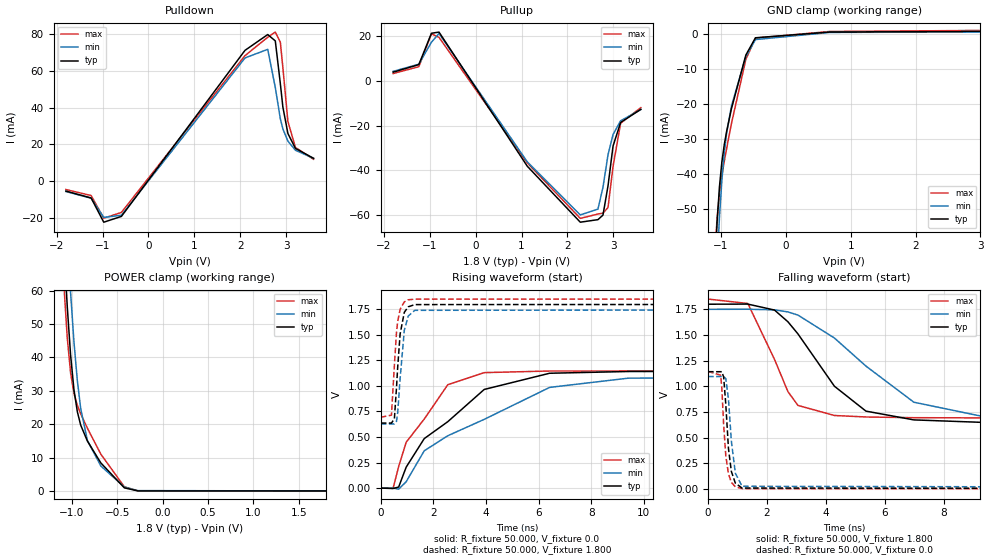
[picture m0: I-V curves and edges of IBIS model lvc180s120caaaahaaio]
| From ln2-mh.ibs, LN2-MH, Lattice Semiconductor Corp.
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|   Model lvc180s120caaaahaaio
[Model] lvc180s120caaaahaaio
| Clamp models do not include dynamic input termination. Please refer to
| the lvc180axxxcaaaahaain model for input termination.
Model_type I/O
Polarity   Non-Inverting
Enable   Active-Low
Vinl =  0.630V
Vinh =  1.170V
Vmeas =  0.900V
Cref =  0.0F
Rref =  1.000M
Vref =  0.0V
C_comp   2.000pF   1.500pF   2.500pF
[Temperature Range]   25.000   0.125k   -40.000
[Voltage Range]   1.800V   1.750V   1.850V
[C Comp Corner]
C_comp   2.000pF   1.500pF   2.500pF
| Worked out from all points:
|   slope of the pulldown table from 0 to 0.27 V, typ, clamps not added: 28 ohm
|   slope of the pullup table from 0 to 0.27 V, typ, clamps not added: 28.4 ohm
|   GND clamp passes 1 mA (typ) near -0.47 V on its own axis
|   POWER clamp passes 1 mA (typ) near -0.42 V on its own axis
|   rising waveform, R_fixture 50.000, V_fixture 0.0: 20-80 % time 2.7ns typ, 4.08ns min, 1.59ns max; typ from 0 V to 1.14 V
|   rising waveform, R_fixture 50.000, V_fixture 1.800: 20-80 % time 192ps typ, 206ps min, 176ps max; typ from 0.637 V to 1.8 V
|   falling waveform, R_fixture 50.000, V_fixture 1.800: 20-80 % time 1.83ns typ, 2.9ns min, 1ns max; typ from 1.8 V to 0.637 V
|   falling waveform, R_fixture 50.000, V_fixture 0.0: 20-80 % time 173ps typ, 191ps min, 161ps max; typ from 1.14 V to 0 V
[Pulldown]
|Voltage   I(typ)   I(min)   I(max)
-1.8V     -5.318mA   -5.577mA   -4.475mA
-1.25V    -9.062mA   -9.182mA   -7.735mA
-975mV    -22.2mA    -19.61mA   -20.03mA
-590mV    -19.06mA   -18.42mA   -16.9mA
2.105V    71.06mA    66.94mA    68.18mA
2.6V      79.61mA    71.59mA    78.17mA
2.765V    76.19mA    50.9mA     80.96mA
2.875V    52.97mA    33.89mA    75.49mA
2.93V     40.32mA    28.45mA    61.75mA
3.04V     25.91mA    21.77mA    32.46mA
3.205V    17.82mA    16.83mA    18.34mA
3.6V      12.45mA    12.45mA    11.93mA
[Pullup]
|Voltage   I(typ)   I(min)   I(max)
-1.8V     3.89mA     4.239mA    3.279mA
-1.24V    7.275mA    7.479mA    6.342mA
-965mV    21.32mA    17.3mA     21.08mA
-800mV    21.84mA    21.21mA    19.49mA
1.125V    -38.23mA   -36.28mA   -36.74mA
2.28V     -63.29mA   -60.03mA   -61.59mA
2.665V    -62.15mA   -57.45mA   -59.64mA
2.775V    -60.12mA   -47.62mA   -59.25mA
2.885V    -46.97mA   -33.07mA   -56.69mA
2.995V    -29.13mA   -24mA      -38.24mA
3.16V     -18.63mA   -17.87mA   -18.95mA
3.6V      -12.75mA   -12.86mA   -12mA
[GND_clamp]
|Voltage   I(typ)   I(min)   I(max)
-1.8V     -571mA     -571.9mA   -573mA
-1.097V   -67.89mA   -81.9mA    -63.82mA
-1.06V    -53.86mA   -65.72mA   -52.69mA
-1.023V   -43.6mA    -52.29mA   -45.48mA
-986mV    -36.55mA   -41.78mA   -40.47mA
-949mV    -31.59mA   -33.97mA   -36.38mA
-912mV    -27.73mA   -28.25mA   -32.63mA
-838mV    -21.28mA   -20.51mA   -25.51mA
-616mV    -5.929mA   -6.389mA   -7.151mA
-468mV    -1.006mA   -1.514mA   -1.077mA
679mV     636.6uA    525.1uA    801uA
3.6V      859.5uA    698.9uA    1.171mA
[POWER_clamp]
|Voltage   I(typ)   I(min)   I(max)
-1.789V   616.8mA    624.1mA    614.9mA
-1.086V   73.72mA    96.92mA    61.82mA
-1.049V   55.3mA     76.94mA    45.93mA
-1.012V   40.68mA    59.35mA    35.33mA
-975mV    30.32mA    44.62mA    29.25mA
-938mV    23.76mA    33.09mA    25.68mA
-901mV    19.73mA    24.71mA    23.1mA
-827mV    14.94mA    15.12mA    18.78mA
-679mV    8.384mA    7.465mA    11.01mA
-420mV    917.4uA    1.181mA    1.232mA
-272mV    19.37uA    92.48uA    11.5uA
1.8V      0A         0A         0A
[Ramp]
| variable   typ   min   max
dV/dt_r   0.686/2.705n   0.657/4.085n   0.688/1.588n
dV/dt_f   0.698/1.832n   0.673/2.907n   0.694/1.007n
R_load = 50.000
[Rising Waveform]
R_fixture= 50.000
V_fixture= 0.0
V_fixture_min= 0.0
V_fixture_max= 0.0
|time   V(typ)   V(min)   V(max)
0s        1.76uV     9.003uV    814.4nV
469ps     -3.923mV   -259.5uV   -2.248mV
681ps     10.55mV    -10.51mV   211.8mV
967ps     205.6mV    62.73mV    448.9mV
1.652ns   484.3mV    364.9mV    675.6mV
2.548ns   650.2mV    512.5mV    1.012V
3.931ns   965.4mV    672.7mV    1.13V
6.416ns   1.124V     985.4mV    1.146V
9.412ns   1.141V     1.076V     1.146V
50ns      1.143V     1.096V     1.146V
[Rising Waveform]
R_fixture= 50.000
V_fixture= 1.800
V_fixture_min= 1.750
V_fixture_max= 1.850
|time   V(typ)   V(min)   V(max)
0s        636.5mV    628.2mV    692.9mV
406ps     635.9mV    628.3mV    714.1mV
518ps     678.4mV    628.4mV    1.201V
597ps     979.6mV    652.8mV    1.522V
645ps     1.189V     740.6mV    1.633V
736ps     1.509V     1.074V     1.749V
895ps     1.72V      1.544V     1.823V
1.042ns   1.774V     1.683V     1.843V
1.294ns   1.796V     1.74V      1.849V
50ns      1.8V       1.75V      1.85V
[Falling Waveform]
R_fixture= 50.000
V_fixture= 1.800
V_fixture_min= 1.750
V_fixture_max= 1.850
|time   V(typ)   V(min)   V(max)
0s        1.8V       1.75V      1.85V
1.351ns   1.801V     1.751V     1.807V
2.256ns   1.743V     1.745V     1.263V
2.711ns   1.629V     1.725V     949.2mV
3.051ns   1.511V     1.694V     815.1mV
4.287ns   1.002V     1.471V     717mV
5.356ns   759.6mV    1.198V     702.5mV
6.982ns   674.1mV    846.1mV    695.6mV
9.79ns    645mV      679.5mV    693.3mV
50ns      636.5mV    628.2mV    692.9mV
[Falling Waveform]
R_fixture= 50.000
V_fixture= 0.0
V_fixture_min= 0.0
V_fixture_max= 0.0
|time   V(typ)   V(min)   V(max)
0s        1.143V     1.096V     1.146V
429ps     1.143V     1.096V     1.109V
467ps     1.143V     1.096V     1V
531ps     1.093V     1.097V     627mV
604ps     824.7mV    1.075V     325.3mV
695ps     394mV      876mV      148.5mV
792ps     173.6mV    469.1mV    66.69mV
928ps     58.54mV    155.8mV    22.88mV
1.155ns   11.03mV    28.12mV    5.305mV
50ns      1.787uV    9.047uV    829.5nV
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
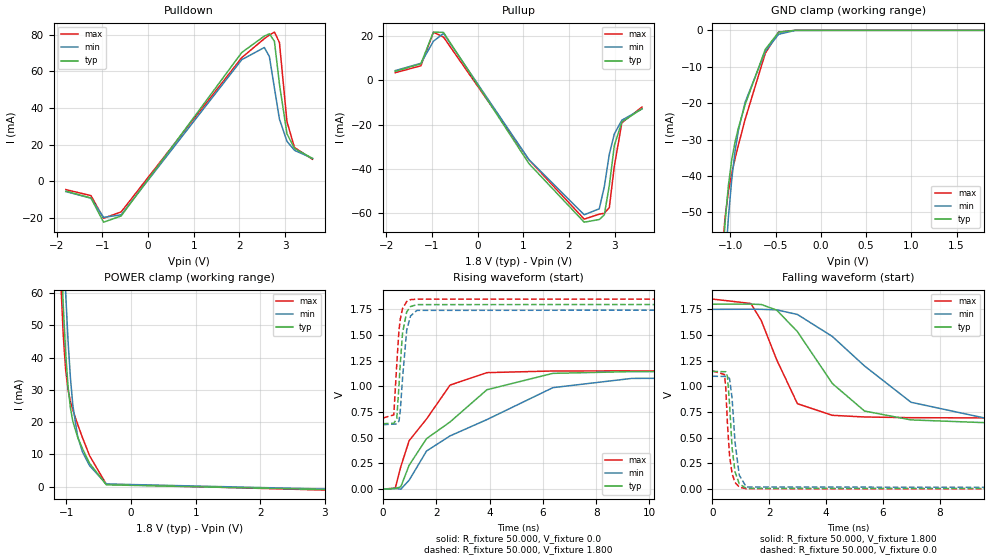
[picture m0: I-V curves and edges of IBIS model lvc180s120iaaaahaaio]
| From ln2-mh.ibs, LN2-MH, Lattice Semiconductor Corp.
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|   Model lvc180s120iaaaahaaio
[Model] lvc180s120iaaaahaaio
| Clamp models do not include dynamic input termination. Please refer to
| the lvc180axxxiaaaahaain model for input termination.
Model_type I/O
Polarity   Non-Inverting
Enable   Active-Low
Vinl =  0.630V
Vinh =  1.170V
Vmeas =  0.900V
Cref =  0.0F
Rref =  1.000M
Vref =  0.0V
C_comp   2.000pF   1.500pF   2.500pF
[Temperature Range]   25.000   0.125k   -40.000
[Voltage Range]   1.800V   1.750V   1.850V
[C Comp Corner]
C_comp   2.000pF   1.500pF   2.500pF
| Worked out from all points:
|   slope of the pulldown table from 0 to 0.27 V, typ, clamps not added: 27.5 ohm
|   slope of the pullup table from 0 to 0.27 V, typ, clamps not added: 28.4 ohm
|   GND clamp passes 1 mA (typ) near -0.50 V on its own axis
|   POWER clamp passes 1 mA (typ) near -0.41 V on its own axis
|   rising waveform, R_fixture 50.000, V_fixture 0.0: 20-80 % time 2.7ns typ, 4.07ns min, 1.58ns max; typ from 0 V to 1.15 V
|   rising waveform, R_fixture 50.000, V_fixture 1.800: 20-80 % time 188ps typ, 203ps min, 172ps max; typ from 0.637 V to 1.8 V
|   falling waveform, R_fixture 50.000, V_fixture 1.800: 20-80 % time 1.83ns typ, 2.9ns min, 1ns max; typ from 1.8 V to 0.637 V
|   falling waveform, R_fixture 50.000, V_fixture 0.0: 20-80 % time 173ps typ, 191ps min, 161ps max; typ from 1.15 V to 0 V
[Pulldown]
|Voltage   I(typ)   I(min)   I(max)
-1.8V     -5.391mA   -5.639mA   -4.557mA
-1.25V    -9.158mA   -9.262mA   -7.842mA
-975mV    -22.35mA   -19.72mA   -20.19mA
-590mV    -18.95mA   -18.33mA   -16.75mA
2.05V     70.28mA    66.37mA    67.48mA
2.545V    79.26mA    73.03mA    77.85mA
2.655V    80.51mA    68.1mA     79.79mA
2.765V    76.43mA    51.02mA    81.44mA
2.875V    53.09mA    33.96mA    75.79mA
3.04V     25.97mA    21.81mA    32.56mA
3.205V    17.86mA    16.87mA    18.4mA
3.6V      12.48mA    12.48mA    11.97mA
[Pullup]
|Voltage   I(typ)   I(min)   I(max)
-1.8V     3.926mA    4.274mA    3.323mA
-1.24V    7.346mA    7.544mA    6.434mA
-965mV    21.59mA    17.48mA    21.54mA
-745mV    21.44mA    20.98mA    19.34mA
1.125V    -37.57mA   -35.77mA   -35.87mA
2.335V    -63.95mA   -60.61mA   -62.57mA
2.665V    -62.74mA   -57.93mA   -60.33mA
2.775V    -60.7mA    -48.02mA   -59.96mA
2.885V    -47.43mA   -33.35mA   -57.38mA
2.995V    -29.42mA   -24.2mA    -38.72mA
3.16V     -18.81mA   -18.03mA   -19.19mA
3.6V      -12.88mA   -12.98mA   -12.15mA
[GND_clamp]
|Voltage   I(typ)   I(min)   I(max)
-1.8V     -569.8mA   -570.8mA   -571.6mA
-1.097V   -66.86mA   -81.02mA   -62.54mA
-1.06V    -52.83mA   -64.84mA   -51.42mA
-1.023V   -42.57mA   -51.42mA   -44.23mA
-986mV    -35.54mA   -40.92mA   -39.25mA
-949mV    -30.61mA   -33.13mA   -35.19mA
-912mV    -26.78mA   -27.43mA   -31.48mA
-838mV    -20.4mA    -19.75mA   -24.45mA
-616mV    -5.27mA    -5.819mA   -6.352mA
-468mV    -506.5uA   -1.081mA   -470.6uA
-283mV    -1.427uA   -17.24uA   -284.7nA
1.8V      0A         0A         0A
[POWER_clamp]
|Voltage   I(typ)   I(min)   I(max)
-1.789V   617.6mA    624.8mA    616.1mA
-1.086V   74.45mA    97.52mA    62.79mA
-1.049V   56mA       77.52mA    46.83mA
-1.012V   41.34mA    59.91mA    36.16mA
-975mV    30.94mA    45.16mA    30mA
-938mV    24.33mA    33.6mA     26.37mA
-901mV    20.25mA    25.2mA     23.75mA
-827mV    15.39mA    15.54mA    19.34mA
-753mV    11.85mA    10.81mA    15.26mA
-642mV    7.266mA    6.521mA    9.605mA
-383mV    595.8uA    860.9uA    753.9uA
3.6V      -1.113mA   -985.8uA   -1.346mA
[Ramp]
| variable   typ   min   max
dV/dt_r   0.688/2.696n   0.659/4.073n   0.691/1.585n
dV/dt_f   0.698/1.833n   0.673/2.911n   0.694/1.006n
R_load = 50.000
[Rising Waveform]
R_fixture= 50.000
V_fixture= 0.0
V_fixture_min= 0.0
V_fixture_max= 0.0
|time   V(typ)   V(min)   V(max)
0s        1.76uV     9.003uV    814.4nV
462ps     5.814mV    7.571mV    10.87mV
671ps     23.54mV    -70.19uV   219.9mV
982ps     232.9mV    87.09mV    471.8mV
1.637ns   491.9mV    371.5mV    683.4mV
2.519ns   654.3mV    518.4mV    1.013V
3.902ns   967.5mV    677mV      1.134V
6.377ns   1.127V     987.9mV    1.15V
9.346ns   1.144V     1.078V     1.151V
50ns      1.146V     1.099V     1.151V
[Rising Waveform]
R_fixture= 50.000
V_fixture= 1.800
V_fixture_min= 1.750
V_fixture_max= 1.850
|time   V(typ)   V(min)   V(max)
0s        636.5mV    628.2mV    692.9mV
406ps     641.8mV    632.9mV    722.4mV
518ps     685.5mV    633.8mV    1.215V
601ps     1.007V     662.2mV    1.548V
649ps     1.219V     760.2mV    1.654V
736ps     1.522V     1.084V     1.759V
891ps     1.725V     1.548V     1.826V
1.036ns   1.777V     1.686V     1.844V
1.273ns   1.796V     1.74V      1.849V
50ns      1.8V       1.75V      1.85V
[Falling Waveform]
R_fixture= 50.000
V_fixture= 1.800
V_fixture_min= 1.750
V_fixture_max= 1.850
|time   V(typ)   V(min)   V(max)
0s        1.8V       1.75V      1.85V
1.351ns   1.801V     1.751V     1.807V
1.72ns    1.797V     1.75V      1.64V
2.26ns    1.743V     1.745V     1.26V
2.991ns   1.533V     1.7V       831.6mV
4.219ns   1.028V     1.486V     718.6mV
5.35ns    760.3mV    1.199V     702.6mV
6.984ns   674.1mV    845.9mV    695.6mV
9.795ns   645mV      679.4mV    693.3mV
50ns      636.5mV    628.2mV    692.9mV
[Falling Waveform]
R_fixture= 50.000
V_fixture= 0.0
V_fixture_min= 0.0
V_fixture_max= 0.0
|time   V(typ)   V(min)   V(max)
0s        1.146V     1.099V     1.151V
424ps     1.143V     1.097V     1.116V
470ps     1.143V     1.096V     986.4mV
530ps     1.095V     1.097V     632.5mV
604ps     824.6mV    1.075V     325.3mV
693ps     400.8mV    883.6mV    151.1mV
794ps     170.7mV    461.8mV    65.61mV
945ps     51.3mV     136.1mV    20.16mV
1.193ns   8.599mV    21.47mV    4.448mV
50ns      1.787uV    9.047uV    829.5nV
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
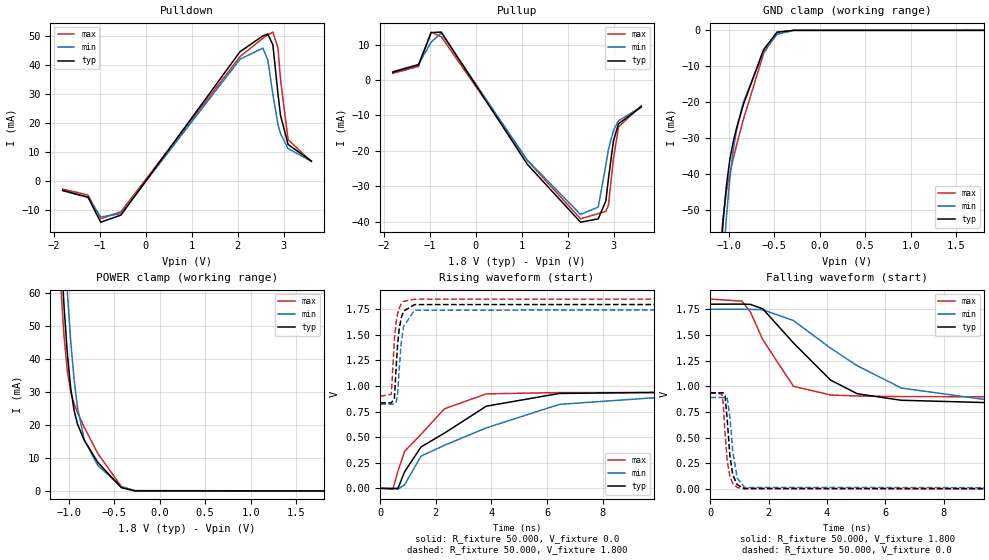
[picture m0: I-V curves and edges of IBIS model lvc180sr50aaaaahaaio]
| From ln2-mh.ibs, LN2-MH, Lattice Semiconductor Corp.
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|   Model lvc180sr50aaaaahaaio
[Model] lvc180sr50aaaaahaaio
| Clamp models do not include dynamic input termination. Please refer to
| the lvc180axxxaaaaahaain model for input termination.
Model_type I/O
Polarity   Non-Inverting
Enable   Active-Low
Vinl =  0.630V
Vinh =  1.170V
Vmeas =  0.900V
Cref =  0.0F
Rref =  1.000M
Vref =  0.0V
C_comp   2.000pF   1.500pF   2.500pF
[Temperature Range]   25.000   0.125k   -40.000
[Voltage Range]   1.800V   1.750V   1.850V
[C Comp Corner]
C_comp   2.000pF   1.500pF   2.500pF
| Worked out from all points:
|   slope of the pulldown table from 0 to 0.27 V, typ, clamps not added: 42.9 ohm
|   slope of the pullup table from 0 to 0.27 V, typ, clamps not added: 44.7 ohm
|   GND clamp passes 1 mA (typ) near -0.49 V on its own axis
|   POWER clamp passes 1 mA (typ) near -0.42 V on its own axis
|   rising waveform, R_fixture 50.000, V_fixture 0.0: 20-80 % time 2.55ns typ, 3.81ns min, 1.54ns max; typ from 0 V to 0.938 V
|   rising waveform, R_fixture 50.000, V_fixture 1.800: 20-80 % time 164ps typ, 179ps min, 155ps max; typ from 0.835 V to 1.8 V
|   falling waveform, R_fixture 50.000, V_fixture 1.800: 20-80 % time 1.93ns typ, 3.08ns min, 1.07ns max; typ from 1.8 V to 0.835 V
|   falling waveform, R_fixture 50.000, V_fixture 0.0: 20-80 % time 173ps typ, 194ps min, 162ps max; typ from 0.937 V to 0 V
[Pulldown]
|Voltage   I(typ)   I(min)   I(max)
-1.8V     -3.205mA   -3.321mA   -2.748mA
-1.25V    -5.576mA   -5.625mA   -4.818mA
-975mV    -14.17mA   -12.38mA   -12.97mA
-535mV    -11.72mA   -11.24mA   -10.57mA
2.05V     44.54mA    41.96mA    42.84mA
2.545V    49.98mA    45.81mA    49.18mA
2.655V    50.66mA    41.76mA    50.38mA
2.765V    46.89mA    29.83mA    51.32mA
2.875V    30.14mA    19.51mA    45.95mA
2.93V     22.69mA    16.35mA    35.23mA
3.095V    12.61mA    11.2mA     14.28mA
3.6V      6.912mA    6.834mA    6.723mA
[Pullup]
|Voltage   I(typ)   I(min)   I(max)
-1.8V     2.179mA    2.351mA    1.868mA
-1.24V    4.296mA    4.402mA    3.813mA
-965mV    13.36mA    10.69mA    13.48mA
-745mV    13.51mA    13.2mA     12.19mA
1.125V    -23.79mA   -22.61mA   -22.73mA
2.28V     -40.11mA   -37.94mA   -39.15mA
2.665V    -39.17mA   -35.83mA   -37.7mA
2.83V     -34.09mA   -23.89mA   -37.03mA
2.885V    -27.92mA   -19.64mA   -35.32mA
2.995V    -17.13mA   -14.25mA   -22.24mA
3.105V    -12.36mA   -11.5mA    -13.23mA
3.6V      -7.572mA   -7.556mA   -7.214mA
[GND_clamp]
|Voltage   I(typ)   I(min)   I(max)
-1.8V     -570.9mA   -571.8mA   -572.9mA
-1.097V   -67.54mA   -81.64mA   -63.35mA
-1.06V    -53.45mA   -65.42mA   -52.13mA
-1.023V   -43.13mA   -51.95mA   -44.86mA
-986mV    -36.04mA   -41.41mA   -39.83mA
-949mV    -31.06mA   -33.56mA   -35.72mA
-912mV    -27.18mA   -27.83mA   -31.97mA
-838mV    -20.73mA   -20.06mA   -24.86mA
-616mV    -5.403mA   -5.958mA   -6.517mA
-468mV    -530.3uA   -1.122mA   -495.6uA
-283mV    -1.808uA   -19.61uA   -457.7nA
1.8V      0A         0A         0A
[POWER_clamp]
|Voltage   I(typ)   I(min)   I(max)
-1.789V   617.6mA    624.8mA    616.1mA
-1.086V   74.43mA    97.5mA     62.76mA
-1.049V   55.98mA    77.5mA     46.8mA
-1.012V   41.32mA    59.89mA    36.12mA
-975mV    30.91mA    45.13mA    29.96mA
-938mV    24.29mA    33.57mA    26.33mA
-901mV    20.21mA    25.16mA    23.7mA
-827mV    15.35mA    15.5mA     19.29mA
-679mV    8.657mA    7.724mA    11.36mA
-420mV    977.9uA    1.256mA    1.313mA
-272mV    22.92uA    106.7uA    14.08uA
1.8V      0A         0A         0A
[Ramp]
| variable   typ   min   max
dV/dt_r   0.563/2.557n   0.535/3.808n   0.562/1.543n
dV/dt_f   0.579/1.942n   0.556/3.080n   0.571/1.073n
R_load = 50.000
[Rising Waveform]
R_fixture= 50.000
V_fixture= 0.0
V_fixture_min= 0.0
V_fixture_max= 0.0
|time   V(typ)   V(min)   V(max)
0s        2.404uV    12.25uV    1.1uV
452ps     -2.633mV   37.24uV    -8.268mV
639ps     656.1uV    -8.033mV   171.4mV
876ps     161.9mV    34.96mV    361.5mV
1.465ns   404.1mV    314.4mV    527.5mV
2.306ns   539mV      420.3mV    777.2mV
3.815ns   803.1mV    591mV      923.4mV
6.447ns   927.5mV    820.8mV    935.9mV
9.718ns   936.9mV    882.8mV    936.2mV
50ns      937.5mV    892.5mV    936.2mV
[Rising Waveform]
R_fixture= 50.000
V_fixture= 1.800
V_fixture_min= 1.750
V_fixture_max= 1.850
|time   V(typ)   V(min)   V(max)
0s        834.8mV    822.8mV    898.8mV
398ps     834.4mV    822.8mV    919.4mV
509ps     882.5mV    822.9mV    1.464V
575ps     1.201V     843.7mV    1.633V
622ps     1.401V     918.1mV    1.705V
680ps     1.556V     1.162V     1.761V
756ps     1.669V     1.428V     1.803V
837ps     1.732V     1.581V     1.827V
1.23ns    1.796V     1.741V     1.849V
50ns      1.8V       1.75V      1.85V
[Falling Waveform]
R_fixture= 50.000
V_fixture= 1.800
V_fixture_min= 1.750
V_fixture_max= 1.850
|time   V(typ)   V(min)   V(max)
0s        1.8V       1.75V      1.85V
1.087ns   1.801V     1.751V     1.83V
1.376ns   1.798V     1.75V      1.724V
1.801ns   1.755V     1.746V     1.454V
2.851ns   1.423V     1.641V     1.001V
4.121ns   1.062V     1.373V     916.8mV
5.041ns   928.4mV    1.201V     906.3mV
6.551ns   865.2mV    984.2mV    900.9mV
9.862ns   839.2mV    854.6mV    899mV
50ns      834.8mV    822.8mV    898.8mV
[Falling Waveform]
R_fixture= 50.000
V_fixture= 0.0
V_fixture_min= 0.0
V_fixture_max= 0.0
|time   V(typ)   V(min)   V(max)
0s        937.5mV    892.4mV    936.2mV
399ps     937.4mV    892.4mV    925mV
444ps     938.2mV    892.4mV    832.1mV
507ps     910.3mV    892.9mV    540mV
582ps     671.9mV    883.2mV    275.6mV
672ps     325.3mV    700.5mV    127.2mV
772ps     140.6mV    367.5mV    55.54mV
923ps     42.33mV    109.6mV    17.02mV
1.172ns   7.151mV    17.26mV    3.209mV
50ns      2.427uV    12.25uV    1.116uV
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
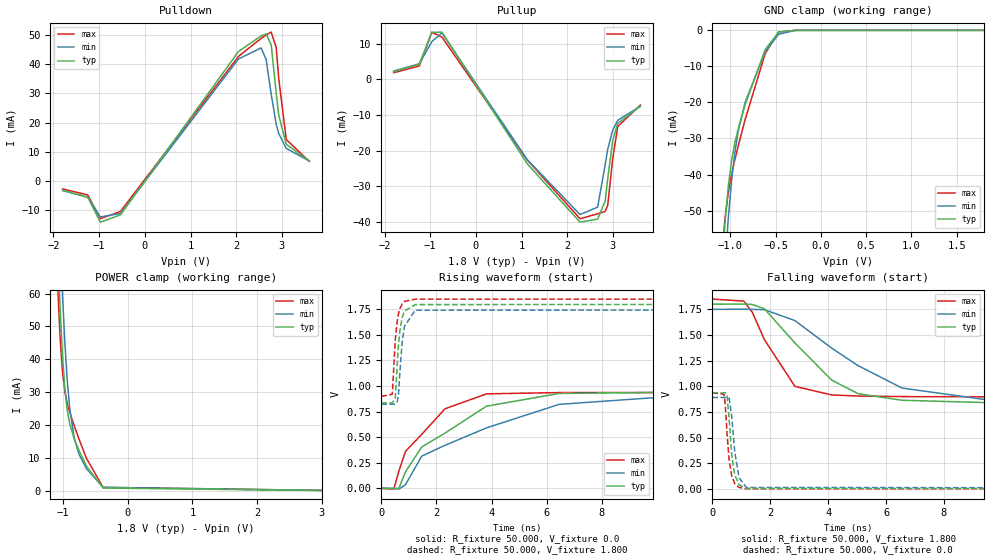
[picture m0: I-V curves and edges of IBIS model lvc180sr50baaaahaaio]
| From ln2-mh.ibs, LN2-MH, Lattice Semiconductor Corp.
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|   Model lvc180sr50baaaahaaio
[Model] lvc180sr50baaaahaaio
| Clamp models do not include dynamic input termination. Please refer to
| the lvc180axxxbaaaahaain model for input termination.
Model_type I/O
Polarity   Non-Inverting
Enable   Active-Low
Vinl =  0.630V
Vinh =  1.170V
Vmeas =  0.900V
Cref =  0.0F
Rref =  1.000M
Vref =  0.0V
C_comp   2.000pF   1.500pF   2.500pF
[Temperature Range]   25.000   0.125k   -40.000
[Voltage Range]   1.800V   1.750V   1.850V
[C Comp Corner]
C_comp   2.000pF   1.500pF   2.500pF
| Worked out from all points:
|   slope of the pulldown table from 0 to 0.27 V, typ, clamps not added: 42.9 ohm
|   slope of the pullup table from 0 to 0.27 V, typ, clamps not added: 45.5 ohm
|   GND clamp passes 1 mA (typ) near -0.50 V on its own axis
|   POWER clamp passes 1 mA (typ) near -0.40 V on its own axis
|   rising waveform, R_fixture 50.000, V_fixture 0.0: 20-80 % time 2.55ns typ, 3.81ns min, 1.54ns max; typ from 0 V to 0.938 V
|   rising waveform, R_fixture 50.000, V_fixture 1.800: 20-80 % time 164ps typ, 179ps min, 155ps max; typ from 0.835 V to 1.8 V
|   falling waveform, R_fixture 50.000, V_fixture 1.800: 20-80 % time 1.93ns typ, 3.08ns min, 1.07ns max; typ from 1.8 V to 0.835 V
|   falling waveform, R_fixture 50.000, V_fixture 0.0: 20-80 % time 173ps typ, 194ps min, 162ps max; typ from 0.937 V to 0 V
[Pulldown]
|Voltage   I(typ)   I(min)   I(max)
-1.8V     -3.201mA   -3.316mA   -2.744mA
-1.25V    -5.569mA   -5.616mA   -4.811mA
-975mV    -14.15mA   -12.35mA   -12.94mA
-535mV    -11.65mA   -11.18mA   -10.5mA
2.05V     44.35mA    41.79mA    42.66mA
2.545V    49.68mA    45.58mA    48.83mA
2.655V    50.36mA    41.56mA    50.03mA
2.765V    46.65mA    29.7mA     50.99mA
2.875V    29.99mA    19.42mA    45.69mA
2.93V     22.57mA    16.27mA    35.05mA
3.095V    12.53mA    11.14mA    14.19mA
3.6V      6.866mA    6.793mA    6.674mA
[Pullup]
|Voltage   I(typ)   I(min)   I(max)
-1.8V     2.133mA    2.309mA    1.821mA
-1.24V    4.215mA    4.333mA    3.727mA
-965mV    13.12mA    10.53mA    13.16mA
-745mV    13.21mA    12.97mA    11.84mA
1.125V    -23.68mA   -22.51mA   -22.63mA
2.28V     -40.02mA   -37.88mA   -39.05mA
2.665V    -39.15mA   -35.8mA    -37.67mA
2.83V     -34.07mA   -23.88mA   -37mA
2.885V    -27.9mA    -19.63mA   -35.3mA
2.995V    -17.12mA   -14.25mA   -22.22mA
3.105V    -12.35mA   -11.49mA   -13.22mA
3.6V      -7.568mA   -7.551mA   -7.21mA
[GND_clamp]
|Voltage   I(typ)   I(min)   I(max)
-1.8V     -570.8mA   -571.7mA   -572.8mA
-1.097V   -67.45mA   -81.54mA   -63.25mA
-1.06V    -53.36mA   -65.33mA   -52.04mA
-1.023V   -43.04mA   -51.86mA   -44.77mA
-986mV    -35.95mA   -41.32mA   -39.74mA
-949mV    -30.97mA   -33.48mA   -35.64mA
-912mV    -27.1mA    -27.74mA   -31.88mA
-838mV    -20.66mA   -19.98mA   -24.78mA
-616mV    -5.345mA   -5.898mA   -6.456mA
-468mV    -515.9uA   -1.096mA   -482.9uA
-283mV    -1.482uA   -17.52uA   -322.5nA
1.8V      0A         0A         0A
[POWER_clamp]
|Voltage   I(typ)   I(min)   I(max)
-1.789V   617.6mA    624.8mA    616.1mA
-1.086V   74.57mA    97.6mA     62.94mA
-1.049V   56.15mA    77.62mA    47.03mA
-1.012V   41.52mA    60.02mA    36.39mA
-975mV    31.15mA    45.29mA    30.27mA
-938mV    24.56mA    33.75mA    26.65mA
-901mV    20.5mA     25.36mA    24.04mA
-827mV    15.64mA    15.72mA    19.63mA
-753mV    12.1mA     11mA       15.55mA
-642mV    7.512mA    6.704mA    9.896mA
-383mV    772.8uA    998.1uA    969uA
3.6V      -108.1uA   -110.5uA   -109.2uA
[Ramp]
| variable   typ   min   max
dV/dt_r   0.563/2.557n   0.535/3.808n   0.562/1.543n
dV/dt_f   0.579/1.942n   0.556/3.080n   0.571/1.073n
R_load = 50.000
[Rising Waveform]
R_fixture= 50.000
V_fixture= 0.0
V_fixture_min= 0.0
V_fixture_max= 0.0
|time   V(typ)   V(min)   V(max)
0s        2.404uV    12.25uV    1.1uV
452ps     -2.633mV   37.24uV    -8.268mV
639ps     656.1uV    -8.033mV   171.4mV
876ps     161.9mV    34.96mV    361.5mV
1.465ns   404.1mV    314.4mV    527.5mV
2.306ns   539mV      420.3mV    777.2mV
3.815ns   803.1mV    591mV      923.4mV
6.447ns   927.5mV    820.8mV    935.9mV
9.718ns   936.9mV    882.8mV    936.2mV
50ns      937.5mV    892.5mV    936.2mV
[Rising Waveform]
R_fixture= 50.000
V_fixture= 1.800
V_fixture_min= 1.750
V_fixture_max= 1.850
|time   V(typ)   V(min)   V(max)
0s        834.8mV    822.8mV    898.8mV
398ps     834.4mV    822.8mV    919.4mV
509ps     882.5mV    822.9mV    1.464V
575ps     1.201V     843.7mV    1.633V
622ps     1.401V     918.1mV    1.705V
680ps     1.556V     1.162V     1.761V
756ps     1.669V     1.428V     1.803V
837ps     1.732V     1.581V     1.827V
1.23ns    1.796V     1.741V     1.849V
50ns      1.8V       1.75V      1.85V
[Falling Waveform]
R_fixture= 50.000
V_fixture= 1.800
V_fixture_min= 1.750
V_fixture_max= 1.850
|time   V(typ)   V(min)   V(max)
0s        1.8V       1.75V      1.85V
1.087ns   1.801V     1.751V     1.83V
1.376ns   1.798V     1.75V      1.724V
1.801ns   1.755V     1.746V     1.454V
2.851ns   1.423V     1.641V     1.001V
4.121ns   1.062V     1.373V     916.8mV
5.041ns   928.4mV    1.201V     906.3mV
6.551ns   865.2mV    984.2mV    900.9mV
9.862ns   839.2mV    854.6mV    899mV
50ns      834.8mV    822.8mV    898.8mV
[Falling Waveform]
R_fixture= 50.000
V_fixture= 0.0
V_fixture_min= 0.0
V_fixture_max= 0.0
|time   V(typ)   V(min)   V(max)
0s        937.5mV    892.4mV    936.2mV
399ps     937.4mV    892.4mV    925mV
444ps     938.2mV    892.4mV    832.1mV
507ps     910.3mV    892.9mV    540mV
582ps     671.9mV    883.2mV    275.6mV
672ps     325.3mV    700.5mV    127.2mV
772ps     140.6mV    367.5mV    55.54mV
923ps     42.33mV    109.6mV    17.02mV
1.172ns   7.151mV    17.26mV    3.209mV
50ns      2.427uV    12.25uV    1.116uV
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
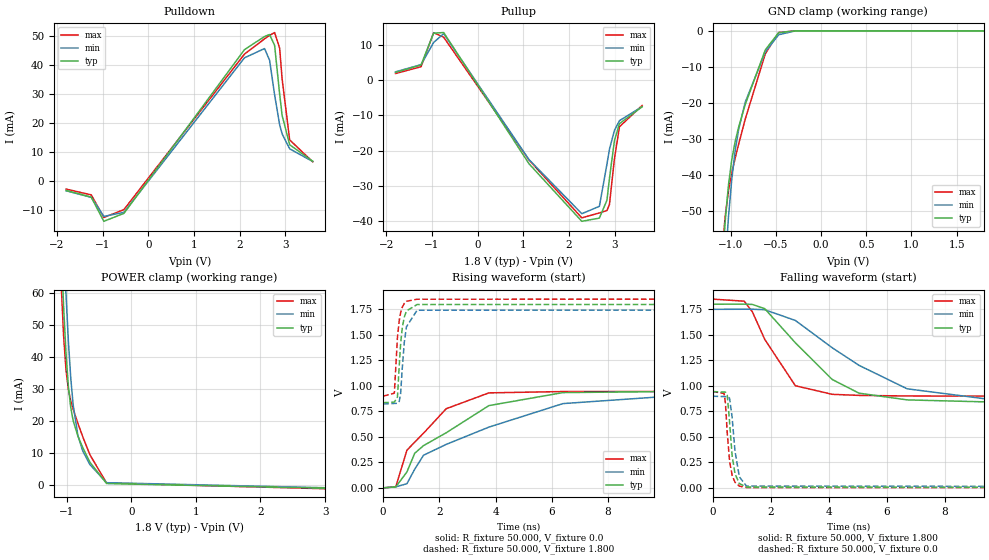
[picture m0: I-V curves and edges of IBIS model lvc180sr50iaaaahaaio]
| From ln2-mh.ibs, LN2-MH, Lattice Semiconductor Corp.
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|   Model lvc180sr50iaaaahaaio
[Model] lvc180sr50iaaaahaaio
| Clamp models do not include dynamic input termination. Please refer to
| the lvc180axxxiaaaahaain model for input termination.
Model_type I/O
Polarity   Non-Inverting
Enable   Active-Low
Vinl =  0.630V
Vinh =  1.170V
Vmeas =  0.900V
Cref =  0.0F
Rref =  1.000M
Vref =  0.0V
C_comp   2.000pF   1.500pF   2.500pF
[Temperature Range]   25.000   0.125k   -40.000
[Voltage Range]   1.800V   1.750V   1.850V
[C Comp Corner]
C_comp   2.000pF   1.500pF   2.500pF
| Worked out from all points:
|   slope of the pulldown table from 0 to 0.27 V, typ, clamps not added: 43.5 ohm
|   slope of the pullup table from 0 to 0.27 V, typ, clamps not added: 44.8 ohm
|   GND clamp passes 1 mA (typ) near -0.50 V on its own axis
|   POWER clamp passes 1 mA (typ) near -0.41 V on its own axis
|   rising waveform, R_fixture 50.000, V_fixture 0.0: 20-80 % time 2.54ns typ, 3.79ns min, 1.53ns max; typ from 0 V to 0.944 V
|   rising waveform, R_fixture 50.000, V_fixture 1.800: 20-80 % time 159ps typ, 175ps min, 150ps max; typ from 0.835 V to 1.8 V
|   falling waveform, R_fixture 50.000, V_fixture 1.800: 20-80 % time 1.94ns typ, 3.08ns min, 1.07ns max; typ from 1.8 V to 0.835 V
|   falling waveform, R_fixture 50.000, V_fixture 0.0: 20-80 % time 174ps typ, 194ps min, 163ps max; typ from 0.944 V to 0 V
[Pulldown]
|Voltage   I(typ)   I(min)   I(max)
-1.8V     -3.152mA   -3.27mA    -2.686mA
-1.25V    -5.466mA   -5.525mA   -4.686mA
-975mV    -13.79mA   -12.1mA    -12.47mA
-535mV    -11.06mA   -10.7mA    -9.758mA
2.105V    45.39mA    42.57mA    43.85mA
2.545V    49.93mA    45.77mA    49.12mA
2.655V    50.61mA    41.72mA    50.33mA
2.765V    46.86mA    29.81mA    51.28mA
2.875V    30.12mA    19.5mA     45.92mA
2.93V     22.67mA    16.33mA    35.21mA
3.095V    12.6mA     11.19mA    14.27mA
3.6V      6.906mA    6.827mA    6.716mA
[Pullup]
|Voltage   I(typ)   I(min)   I(max)
-1.8V     2.179mA    2.351mA    1.868mA
-1.24V    4.297mA    4.403mA    3.814mA
-965mV    13.36mA    10.69mA    13.48mA
-745mV    13.51mA    13.2mA     12.19mA
1.125V    -23.78mA   -22.6mA    -22.72mA
2.28V     -40.11mA   -37.95mA   -39.13mA
2.665V    -39.2mA    -35.86mA   -37.73mA
2.83V     -34.14mA   -23.93mA   -37.06mA
2.885V    -27.98mA   -19.66mA   -35.38mA
2.995V    -17.15mA   -14.28mA   -22.31mA
3.105V    -12.37mA   -11.51mA   -13.25mA
3.6V      -7.574mA   -7.557mA   -7.216mA
[GND_clamp]
|Voltage   I(typ)   I(min)   I(max)
-1.8V     -569.8mA   -570.8mA   -571.6mA
-1.097V   -66.86mA   -81.02mA   -62.54mA
-1.06V    -52.83mA   -64.84mA   -51.42mA
-1.023V   -42.57mA   -51.42mA   -44.23mA
-986mV    -35.54mA   -40.92mA   -39.25mA
-949mV    -30.61mA   -33.13mA   -35.19mA
-912mV    -26.78mA   -27.43mA   -31.48mA
-838mV    -20.4mA    -19.75mA   -24.45mA
-616mV    -5.27mA    -5.819mA   -6.352mA
-468mV    -506.6uA   -1.081mA   -470.6uA
-283mV    -1.427uA   -17.24uA   -284.7nA
1.8V      0A         0A         0A
[POWER_clamp]
|Voltage   I(typ)   I(min)   I(max)
-1.789V   617.6mA    624.8mA    616.1mA
-1.086V   74.45mA    97.52mA    62.79mA
-1.049V   56mA       77.52mA    46.83mA
-1.012V   41.34mA    59.91mA    36.16mA
-975mV    30.94mA    45.16mA    30mA
-938mV    24.33mA    33.6mA     26.37mA
-901mV    20.25mA    25.2mA     23.75mA
-827mV    15.39mA    15.54mA    19.34mA
-753mV    11.85mA    10.81mA    15.26mA
-642mV    7.266mA    6.521mA    9.605mA
-383mV    595.8uA    860.9uA    753.9uA
3.6V      -1.113mA   -985.8uA   -1.346mA
[Ramp]
| variable   typ   min   max
dV/dt_r   0.566/2.542n   0.539/3.789n   0.567/1.532n
dV/dt_f   0.579/1.943n   0.556/3.090n   0.571/1.072n
R_load = 50.000
[Rising Waveform]
R_fixture= 50.000
V_fixture= 0.0
V_fixture_min= 0.0
V_fixture_max= 0.0
|time   V(typ)   V(min)   V(max)
0s        2.404uV    12.25uV    1.1uV
449ps     9.511mV    9.684mV    10.88mV
845ps     155.6mV    40.44mV    368.3mV
1.124ns   339.5mV    183.1mV    448.7mV
1.437ns   413.9mV    319.7mV    535.7mV
2.245ns   540.2mV    426.3mV    775.9mV
3.764ns   806.3mV    595.3mV    931.1mV
6.398ns   933.7mV    825.9mV    944.1mV
9.668ns   943.2mV    888.5mV    944.4mV
50ns      943.8mV    898.2mV    944.4mV
[Rising Waveform]
R_fixture= 50.000
V_fixture= 1.800
V_fixture_min= 1.750
V_fixture_max= 1.850
|time   V(typ)   V(min)   V(max)
0s        834.8mV    822.8mV    898.8mV
398ps     840.6mV    827.4mV    928.1mV
509ps     890.1mV    828.6mV    1.477V
575ps     1.211V     849.9mV    1.646V
622ps     1.413V     925.3mV    1.716V
680ps     1.567V     1.171V     1.77V
750ps     1.672V     1.421V     1.807V
829ps     1.734V     1.579V     1.829V
1.207ns   1.797V     1.741V     1.849V
50ns      1.8V       1.75V      1.85V
[Falling Waveform]
R_fixture= 50.000
V_fixture= 1.800
V_fixture_min= 1.750
V_fixture_max= 1.850
|time   V(typ)   V(min)   V(max)
0s        1.8V       1.75V      1.85V
1.089ns   1.801V     1.751V     1.83V
1.372ns   1.798V     1.751V     1.726V
1.799ns   1.756V     1.746V     1.455V
2.852ns   1.422V     1.641V     1.001V
4.122ns   1.062V     1.373V     916.8mV
5.042ns   928.3mV    1.201V     906.3mV
6.698ns   862.3mV    971.1mV    900.7mV
9.898ns   839.1mV    854.1mV    899mV
50ns      834.8mV    822.8mV    898.8mV
[Falling Waveform]
R_fixture= 50.000
V_fixture= 0.0
V_fixture_min= 0.0
V_fixture_max= 0.0
|time   V(typ)   V(min)   V(max)
0s        943.8mV    898.2mV    944.4mV
399ps     939mV      895mV      925.9mV
444ps     939.2mV    894mV      832.6mV
507ps     910.8mV    893.8mV    540.3mV
587ps     650.1mV    879.8mV    263.8mV
674ps     319.6mV    694.2mV    125.1mV
775ps     137.3mV    359mV      54.25mV
925ps     41.72mV    107.9mV    16.78mV
1.167ns   7.384mV    17.89mV    3.296mV
50ns      2.427uV    12.25uV    1.116uV
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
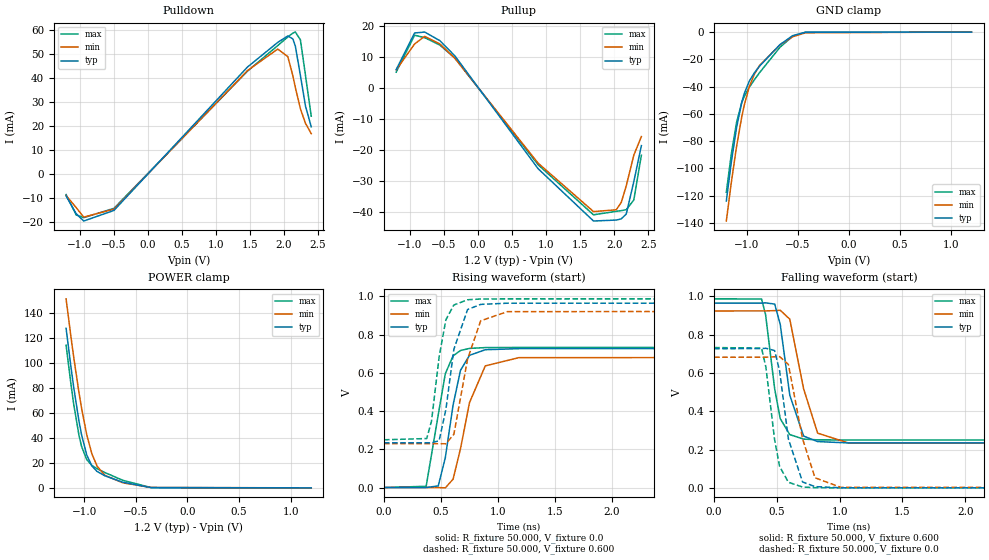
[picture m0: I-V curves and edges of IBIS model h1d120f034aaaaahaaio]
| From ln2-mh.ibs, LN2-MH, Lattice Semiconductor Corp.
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|   Model h1d120f034aaaaahaaio
[Model] h1d120f034aaaaahaaio
| Clamp models do not include dynamic input termination. Please refer to
| the h1d120axxxaaaaahaain model for input termination.
Model_type I/O
Polarity   Non-Inverting
Enable   Active-Low
Vinl =  0.500V
Vinh =  0.700V
Vmeas =  0.600V
Cref =  20.000pF
Rref =  50.000
Vref =  0.600V
C_comp   2.000pF   1.500pF   2.500pF
[Temperature Range]   25.000   0.125k   -40.000
[Voltage Range]   1.200V   1.160V   1.240V
[C Comp Corner]
C_comp   2.000pF   1.500pF   2.500pF
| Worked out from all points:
|   slope of the pulldown table from 0 to 0.18 V, typ, clamps not added: 31.9 ohm
|   slope of the pullup table from 0 to 0.18 V, typ, clamps not added: 32.3 ohm
|   GND clamp passes 1 mA (typ) near -0.49 V on its own axis
|   POWER clamp passes 1 mA (typ) near -0.45 V on its own axis
|   rising waveform, R_fixture 50.000, V_fixture 0.0: 20-80 % time 120ps typ, 148ps min, 109ps max; typ from 0 V to 0.727 V
|   rising waveform, R_fixture 50.000, V_fixture 0.600: 20-80 % time 107ps typ, 128ps min, 99.1ps max; typ from 0.234 V to 0.965 V
|   falling waveform, R_fixture 50.000, V_fixture 0.600: 20-80 % time 97.6ps typ, 125ps min, 89.5ps max; typ from 0.965 V to 0.234 V
|   falling waveform, R_fixture 50.000, V_fixture 0.0: 20-80 % time 94ps typ, 118ps min, 87.2ps max; typ from 0.727 V to 0 V
[Pulldown]
|Voltage   I(typ)   I(min)   I(max)
-1.2V     -9.028mA   -8.849mA   -8.433mA
-1.052V   -16.37mA   -13.85mA   -16.9mA
-941mV    -19.44mA   -17.82mA   -18.04mA
-497mV    -15.03mA   -14.49mA   -14.16mA
1.464V    44.67mA    43.19mA    42.97mA
1.908V    54.92mA    52.15mA    53.6mA
2.056V    57.61mA    48.99mA    57.18mA
2.13V     56.38mA    41.05mA    58.81mA
2.167V    53.35mA    36.11mA    59.24mA
2.241V    41.15mA    27.29mA    55.97mA
2.315V    28.48mA    21.26mA    41.29mA
2.4V      19.77mA    16.93mA    24.21mA
[Pullup]
|Voltage   I(typ)   I(min)   I(max)
-1.2V     6.003mA    5.923mA    5.177mA
-930mV    17.83mA    14.28mA    17.11mA
-782mV    18.14mA    16.75mA    16.33mA
-560mV    15.37mA    14.31mA    13.94mA
-338mV    10.42mA    9.655mA    9.718mA
883mV     -26mA      -24.21mA   -24.72mA
1.697V    -42.92mA   -39.87mA   -40.92mA
2.03V     -42.61mA   -39.3mA    -39.79mA
2.104V    -42.24mA   -36.95mA   -39.57mA
2.178V    -40.66mA   -31.58mA   -39.26mA
2.289V    -30.22mA   -21.65mA   -36.13mA
2.4V      -18.57mA   -15.64mA   -21.69mA
[GND_clamp]
|Voltage   I(typ)   I(min)   I(max)
-1.2V     -123.9mA   -138.6mA   -117.5mA
-1.15V    -94.79mA   -109.7mA   -88.79mA
-1.1V     -70.21mA   -84.06mA   -66.34mA
-1.05V    -51.83mA   -62.6mA    -51.99mA
-1.025V   -45.19mA   -53.76mA   -47.33mA
-975mV    -35.96mA   -40.02mA   -40.53mA
-925mV    -29.87mA   -30.82mA   -34.98mA
-875mV    -25.03mA   -24.57mA   -29.81mA
-675mV    -9.23mA    -9.413mA   -11.2mA
-550mV    -2.635mA   -3.443mA   -3.06mA
-425mV    -169.7uA   -547.4uA   -117uA
1.2V      0A         0A         0A
[POWER_clamp]
|Voltage   I(typ)   I(min)   I(max)
-1.175V   127.9mA    151.5mA    114.3mA
-1.125V   95.1mA     119.3mA    81.28mA
-1.1V     80mA       104.2mA    66.46mA
-1.05V    53.45mA    76.25mA    42.06mA
-1.025V   42.52mA    63.79mA    33.25mA
-975mV    26.42mA    42.64mA    22.65mA
-925mV    17.53mA    27.24mA    17.97mA
-875mV    13.15mA    17.46mA    15.37mA
-800mV    9.709mA    10.06mA    12.3mA
-625mV    4.479mA    4.015mA    6.021mA
-350mV    147.7uA    296.5uA    176.7uA
1.2V      0A         0A         0A
[Ramp]
| variable   typ   min   max
dV/dt_r   0.436/0.121n   0.409/0.148n   0.440/0.109n
dV/dt_f   0.439/0.105n   0.421/0.138n   0.444/92.933p
R_load = 50.000
[Rising Waveform]
R_fixture= 50.000
V_fixture= 0.0
V_fixture_min= 0.0
V_fixture_max= 0.0
|time   V(typ)   V(min)   V(max)
0s        1.021uV    5.586uV    466.9nV
370ps     56.79uV    42.04uV    6.352mV
476ps     8.331mV    -364.1uV   380.8mV
538ps     156.2mV    -1.729mV   595.5mV
606ps     431.5mV    43.65mV    689mV
671ps     613.1mV    202.9mV    716.7mV
750ps     691.5mV    444.3mV    727.8mV
888ps     720.8mV    636.2mV    732mV
1.182ns   726.4mV    679.4mV    732.6mV
10ns      726.5mV    682.1mV    732.6mV
[Rising Waveform]
R_fixture= 50.000
V_fixture= 0.600
V_fixture_min= 0.583
V_fixture_max= 0.619
|time   V(typ)   V(min)   V(max)
0s        233.9mV    229.5mV    249.7mV
375ps     234mV      229.6mV    256.3mV
417ps     233.5mV    229.6mV    347.3mV
484ps     245.6mV    229.1mV    685.1mV
543ps     408.7mV    228.9mV    877.8mV
613ps     723.5mV    278.5mV    954.9mV
733ps     931.1mV    671.8mV    982.2mV
848ps     958mV      872.3mV    986.2mV
1.082ns   964.3mV    920.1mV    986.9mV
10ns      964.5mV    923.8mV    986.9mV
[Falling Waveform]
R_fixture= 50.000
V_fixture= 0.600
V_fixture_min= 0.583
V_fixture_max= 0.619
|time   V(typ)   V(min)   V(max)
0s        964.5mV    923.8mV    986.9mV
378ps     964.8mV    923.9mV    986.3mV
410ps     966.2mV    924mV      905.7mV
483ps     959.5mV    925.5mV    515.6mV
527ps     853.8mV    927.3mV    361.3mV
603ps     484.3mV    880.9mV    278.1mV
713ps     270.4mV    517.4mV    254.6mV
825ps     241.6mV    285.6mV    250.7mV
1.074ns   234.5mV    233.4mV    249.7mV
10ns      233.9mV    229.5mV    249.7mV
[Falling Waveform]
R_fixture= 50.000
V_fixture= 0.0
V_fixture_min= 0.0
V_fixture_max= 0.0
|time   V(typ)   V(min)   V(max)
0s        726.5mV    682.1mV    732.6mV
378ps     727.1mV    682.1mV    730mV
413ps     729mV      682.4mV    629.4mV
482ps     717mV      684.4mV    251.9mV
522ps     611mV      685.4mV    111.5mV
592ps     254.9mV    644.4mV    29.25mV
705ps     30.75mV    255.7mV    4.287mV
804ps     6.376mV    52.47mV    877.6uV
1.009ns   376.6uV    2.863mV    -6.739uV
10ns      1.019uV    5.574uV    471.2nV
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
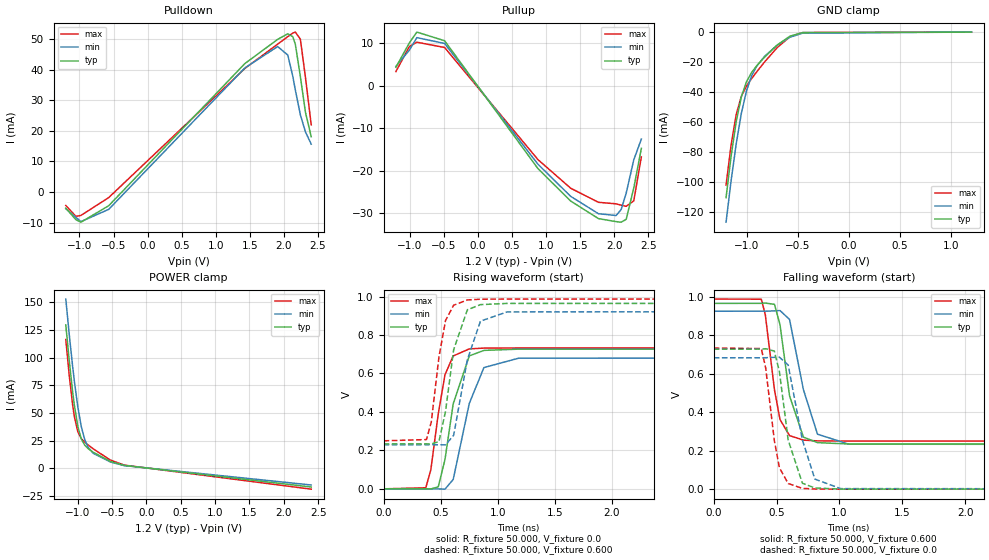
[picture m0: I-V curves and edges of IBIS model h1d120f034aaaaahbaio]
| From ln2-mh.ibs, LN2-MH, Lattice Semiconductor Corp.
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|   Model h1d120f034aaaaahbaio
[Model] h1d120f034aaaaahbaio
| Clamp models do not include dynamic input termination. Please refer to
| the h1d120axxxaaaaahbain model for input termination.
Model_type I/O
Polarity   Non-Inverting
Enable   Active-Low
Vinl =  0.500V
Vinh =  0.700V
Vmeas =  0.600V
Cref =  20.000pF
Rref =  50.000
Vref =  0.600V
C_comp   2.000pF   1.500pF   2.500pF
[Temperature Range]   25.000   0.125k   -40.000
[Voltage Range]   1.200V   1.160V   1.240V
[C Comp Corner]
C_comp   2.000pF   1.500pF   2.500pF
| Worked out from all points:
|   slope of the pulldown table from 0 to 0.18 V, typ, clamps not added: 41.2 ohm
|   slope of the pullup table from 0 to 0.18 V, typ, clamps not added: 42.3 ohm
|   GND clamp passes 1 mA (typ) near -0.51 V on its own axis
|   POWER clamp passes 1 mA (typ) near -0.14 V on its own axis
|   rising waveform, R_fixture 50.000, V_fixture 0.0: 20-80 % time 120ps typ, 148ps min, 109ps max; typ from 0 V to 0.727 V
|   rising waveform, R_fixture 50.000, V_fixture 0.600: 20-80 % time 107ps typ, 128ps min, 99.1ps max; typ from 0.234 V to 0.965 V
|   falling waveform, R_fixture 50.000, V_fixture 0.600: 20-80 % time 97.6ps typ, 125ps min, 89.5ps max; typ from 0.965 V to 0.234 V
|   falling waveform, R_fixture 50.000, V_fixture 0.0: 20-80 % time 94ps typ, 118ps min, 87.2ps max; typ from 0.727 V to 0 V
[Pulldown]
|Voltage   I(typ)   I(min)   I(max)
-1.2V     -5.234mA   -5.457mA   -4.39mA
-1.052V   -9.026mA   -8.255mA   -7.934mA
-978mV    -9.838mA   -9.643mA   -7.631mA
-571mV    -4.469mA   -5.658mA   -1.811mA
1.427V    41.96mA    40.53mA    40.36mA
1.908V    49.86mA    47.51mA    48.3mA
2.056V    51.69mA    44.73mA    50.75mA
2.13V     50.72mA    37.75mA    51.9mA
2.167V    48.26mA    33.3mA     52.23mA
2.241V    37.64mA    25.21mA    49.9mA
2.315V    26.09mA    19.65mA    37.49mA
2.4V      18.06mA    15.64mA    21.94mA
[Pullup]
|Voltage   I(typ)   I(min)   I(max)
-1.2V     4.297mA    4.507mA    3.288mA
-1.004V   9.99mA     8.279mA    9.131mA
-893mV    12.55mA    11.25mA    10.18mA
-486mV    10.52mA    9.881mA    8.929mA
883mV     -19.5mA    -18.47mA   -17.39mA
1.364V    -27.13mA   -26.03mA   -24.12mA
1.771V    -31.25mA   -30.1mA    -27.42mA
2.03V     -31.96mA   -30.52mA   -27.78mA
2.104V    -32.09mA   -29.11mA   -28.09mA
2.178V    -31.41mA   -25.24mA   -28.36mA
2.289V    -24.05mA   -17.44mA   -27.07mA
2.4V      -14.77mA   -12.57mA   -16.75mA
[GND_clamp]
|Voltage   I(typ)   I(min)   I(max)
-1.2V     -110.5mA   -126.9mA   -102.1mA
-1.15V    -82.61mA   -98.92mA   -75.02mA
-1.1V     -59.6mA    -74.29mA   -54.81mA
-1.05V    -43.14mA   -54.12mA   -42.79mA
-1V       -33.07mA   -39.19mA   -36mA
-950mV    -26.96mA   -29.2mA    -31.01mA
-900mV    -22.5mA    -22.72mA   -26.51mA
-825mV    -16.83mA   -16.31mA   -20.09mA
-700mV    -8.624mA   -8.747mA   -10.35mA
-575mV    -2.729mA   -3.404mA   -3.138mA
-450mV    -329.9uA   -671.5uA   -314.7uA
1.2V      0A         0A         0A
[POWER_clamp]
|Voltage   I(typ)   I(min)   I(max)
-1.175V   129.7mA    153.1mA    116.5mA
-1.125V   97.38mA    121.1mA    84.03mA
-1.075V   68.95mA    91.87mA    57.04mA
-1.05V    56.8mA     78.59mA    46.6mA
-1V       37.88mA    55.44mA    33mA
-950mV    26.6mA     37.77mA    26.8mA
-900mV    20.86mA    25.93mA    23.51mA
-850mV    17.67mA    18.89mA    20.97mA
-775mV    14.35mA    13.39mA    17.46mA
-525mV    6.002mA    5.504mA    7.27mA
-325mV    2.453mA    2.285mA    2.745mA
2.4V      -17.13mA   -15.3mA    -19.07mA
[Ramp]
| variable   typ   min   max
dV/dt_r   0.436/0.120n   0.409/0.148n   0.440/0.109n
dV/dt_f   0.439/0.105n   0.421/0.138n   0.444/92.933p
R_load = 50.000
[Rising Waveform]
R_fixture= 50.000
V_fixture= 0.0
V_fixture_min= 0.0
V_fixture_max= 0.0
|time   V(typ)   V(min)   V(max)
0s        1.021uV    5.586uV    466.9nV
369ps     59.81uV    41.66uV    5.464mV
413ps     -518.2uV   68.8uV     98.66mV
478ps     10.24mV    -394.1uV   389.3mV
537ps     152.6mV    -1.688mV   593.1mV
609ps     442.1mV    48.66mV    691.1mV
750ps     691.5mV    444.3mV    727.8mV
878ps     720mV      630.7mV    731.9mV
1.182ns   726.4mV    679.4mV    732.6mV
10ns      726.5mV    682.1mV    732.6mV
[Rising Waveform]
R_fixture= 50.000
V_fixture= 0.600
V_fixture_min= 0.583
V_fixture_max= 0.619
|time   V(typ)   V(min)   V(max)
0s        233.9mV    229.5mV    249.7mV
375ps     234mV      229.6mV    256.3mV
417ps     233.5mV    229.6mV    347.3mV
484ps     245.6mV    229.1mV    685.1mV
542ps     404mV      228.9mV    875.7mV
613ps     723.5mV    278.5mV    954.9mV
733ps     931.1mV    671.8mV    982.2mV
848ps     958mV      872.3mV    986.2mV
1.082ns   964.3mV    920.1mV    986.9mV
10ns      964.5mV    923.8mV    986.9mV
[Falling Waveform]
R_fixture= 50.000
V_fixture= 0.600
V_fixture_min= 0.583
V_fixture_max= 0.619
|time   V(typ)   V(min)   V(max)
0s        964.5mV    923.8mV    986.9mV
378ps     964.8mV    923.9mV    986.3mV
410ps     966.2mV    924mV      905.7mV
483ps     959.5mV    925.5mV    515.6mV
527ps     853.8mV    927.3mV    361.3mV
603ps     484.3mV    880.9mV    278.1mV
713ps     270.4mV    517.4mV    254.6mV
825ps     241.6mV    285.6mV    250.7mV
1.074ns   234.5mV    233.4mV    249.7mV
10ns      233.9mV    229.5mV    249.7mV
[Falling Waveform]
R_fixture= 50.000
V_fixture= 0.0
V_fixture_min= 0.0
V_fixture_max= 0.0
|time   V(typ)   V(min)   V(max)
0s        726.5mV    682.1mV    732.6mV
378ps     727.1mV    682.1mV    730mV
413ps     729mV      682.4mV    629.4mV
482ps     717mV      684.4mV    251.9mV
522ps     611mV      685.4mV    111.5mV
592ps     254.9mV    644.4mV    29.25mV
705ps     30.75mV    255.7mV    4.287mV
804ps     6.376mV    52.47mV    877.6uV
1.009ns   376.6uV    2.863mV    -6.739uV
10ns      1.019uV    5.574uV    471.2nV
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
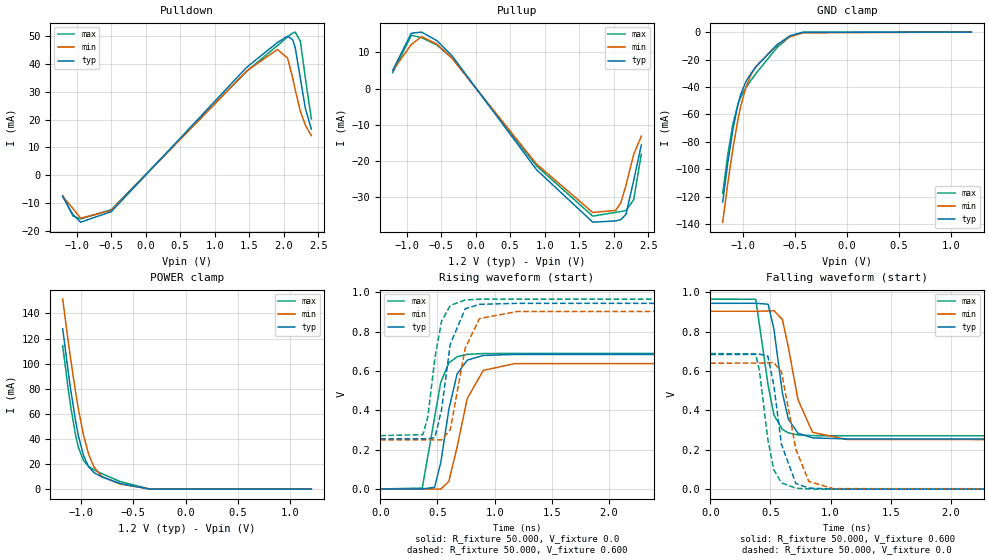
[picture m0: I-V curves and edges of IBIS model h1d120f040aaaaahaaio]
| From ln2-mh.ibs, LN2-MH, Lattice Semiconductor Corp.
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|   Model h1d120f040aaaaahaaio
[Model] h1d120f040aaaaahaaio
| Clamp models do not include dynamic input termination. Please refer to
| the h1d120axxxaaaaahaain model for input termination.
Model_type I/O
Polarity   Non-Inverting
Enable   Active-Low
Vinl =  0.500V
Vinh =  0.700V
Vmeas =  0.600V
Cref =  20.000pF
Rref =  50.000
Vref =  0.600V
C_comp   2.000pF   1.500pF   2.500pF
[Temperature Range]   25.000   0.125k   -40.000
[Voltage Range]   1.200V   1.160V   1.240V
[C Comp Corner]
C_comp   2.000pF   1.500pF   2.500pF
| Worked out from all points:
|   slope of the pulldown table from 0 to 0.18 V, typ, clamps not added: 36.9 ohm
|   slope of the pullup table from 0 to 0.18 V, typ, clamps not added: 37.3 ohm
|   GND clamp passes 1 mA (typ) near -0.49 V on its own axis
|   POWER clamp passes 1 mA (typ) near -0.45 V on its own axis
|   rising waveform, R_fixture 50.000, V_fixture 0.0: 20-80 % time 120ps typ, 148ps min, 110ps max; typ from 0 V to 0.684 V
|   rising waveform, R_fixture 50.000, V_fixture 0.600: 20-80 % time 104ps typ, 126ps min, 98.2ps max; typ from 0.255 V to 0.943 V
|   falling waveform, R_fixture 50.000, V_fixture 0.600: 20-80 % time 100ps typ, 128ps min, 92.7ps max; typ from 0.943 V to 0.255 V
|   falling waveform, R_fixture 50.000, V_fixture 0.0: 20-80 % time 96.8ps typ, 120ps min, 90.9ps max; typ from 0.684 V to 0 V
[Pulldown]
|Voltage   I(typ)   I(min)   I(max)
-1.2V     -7.7mA     -7.547mA   -7.213mA
-1.052V   -14.04mA   -11.86mA   -14.56mA
-941mV    -16.77mA   -15.34mA   -15.61mA
-497mV    -13.01mA   -12.54mA   -12.27mA
1.464V    38.7mA     37.38mA    37.29mA
1.908V    47.55mA    45.07mA    46.48mA
2.056V    49.83mA    42.04mA    49.58mA
2.13V     48.57mA    34.91mA    50.98mA
2.167V    45.71mA    30.58mA    51.31mA
2.241V    34.72mA    23.01mA    48.07mA
2.315V    23.86mA    17.9mA     34.67mA
2.4V      16.59mA    14.23mA    20.22mA
[Pullup]
|Voltage   I(typ)   I(min)   I(max)
-1.2V     5.078mA    5mA        4.396mA
-930mV    15.33mA    12.22mA    14.77mA
-782mV    15.65mA    14.42mA    14.12mA
-560mV    13.27mA    12.33mA    12.06mA
-338mV    9.009mA    8.335mA    8.419mA
883mV     -22.47mA   -20.9mA    -21.41mA
1.697V    -36.99mA   -34.31mA   -35.32mA
2.03V     -36.63mA   -33.7mA    -34.25mA
2.104V    -36.28mA   -31.58mA   -34.04mA
2.178V    -34.81mA   -26.8mA    -33.74mA
2.289V    -25.48mA   -18.25mA   -30.79mA
2.4V      -15.6mA    -13.17mA   -18.13mA
[GND_clamp]
|Voltage   I(typ)   I(min)   I(max)
-1.2V     -123.9mA   -138.6mA   -117.5mA
-1.15V    -94.79mA   -109.7mA   -88.79mA
-1.1V     -70.21mA   -84.05mA   -66.33mA
-1.05V    -51.83mA   -62.6mA    -51.98mA
-1.025V   -45.19mA   -53.76mA   -47.33mA
-975mV    -35.96mA   -40.02mA   -40.52mA
-925mV    -29.87mA   -30.81mA   -34.98mA
-875mV    -25.03mA   -24.57mA   -29.81mA
-675mV    -9.229mA   -9.413mA   -11.2mA
-550mV    -2.635mA   -3.442mA   -3.059mA
-425mV    -169.7uA   -547.4uA   -117uA
1.2V      0A         0A         0A
[POWER_clamp]
|Voltage   I(typ)   I(min)   I(max)
-1.175V   127.9mA    151.5mA    114.3mA
-1.125V   95.1mA     119.3mA    81.28mA
-1.1V     80mA       104.2mA    66.46mA
-1.05V    53.45mA    76.25mA    42.06mA
-1.025V   42.52mA    63.79mA    33.25mA
-975mV    26.42mA    42.64mA    22.65mA
-925mV    17.53mA    27.24mA    17.97mA
-875mV    13.15mA    17.46mA    15.37mA
-800mV    9.709mA    10.06mA    12.3mA
-625mV    4.479mA    4.015mA    6.021mA
-350mV    147.7uA    296.5uA    176.7uA
1.2V      0A         0A         0A
[Ramp]
| variable   typ   min   max
dV/dt_r   0.410/0.120n   0.384/0.149n   0.413/0.110n
dV/dt_f   0.414/0.108n   0.397/0.142n   0.418/95.414p
R_load = 50.000
[Rising Waveform]
R_fixture= 50.000
V_fixture= 0.0
V_fixture_min= 0.0
V_fixture_max= 0.0
|time   V(typ)   V(min)   V(max)
0s        1.134uV    6.183uV    517.4nV
367ps     64.77uV    45.5uV     4.083mV
475ps     8.217mV    -325.3uV   362.8mV
529ps     133.5mV    -1.152mV   542.3mV
600ps     405.7mV    38.64mV    640.8mV
672ps     584mV      213.2mV    672.2mV
761ps     654.7mV    460mV      684.1mV
901ps     678.7mV    602.5mV    688.2mV
1.174ns   683.5mV    636.9mV    688.7mV
10ns      683.6mV    639.6mV    688.7mV
[Rising Waveform]
R_fixture= 50.000
V_fixture= 0.600
V_fixture_min= 0.583
V_fixture_max= 0.619
|time   V(typ)   V(min)   V(max)
0s        254.7mV    249.8mV    271mV
373ps     254.8mV    249.9mV    276mV
416ps     254.3mV    249.9mV    366.3mV
478ps     261.7mV    249.5mV    666.4mV
536ps     403mV      249.6mV    852.7mV
612ps     735.5mV    300.4mV    932.7mV
743ps     916mV      716mV      960.8mV
868ps     938.4mV    866mV      964.6mV
1.196ns   943.4mV    901.9mV    965.2mV
10ns      943.4mV    903.1mV    965.2mV
[Falling Waveform]
R_fixture= 50.000
V_fixture= 0.600
V_fixture_min= 0.583
V_fixture_max= 0.619
|time   V(typ)   V(min)   V(max)
0s        943.4mV    903.1mV    965.1mV
378ps     943.7mV    903.1mV    964mV
481ps     938.9mV    904.6mV    527.5mV
529ps     813.4mV    906.3mV    377.1mV
599ps     491.1mV    862mV      303.6mV
649ps     355.7mV    721.6mV    285.9mV
729ps     283.8mV    454.8mV    275.4mV
850ps     260.5mV    288.5mV    271.8mV
1.137ns   255mV      252.1mV    271mV
10ns      254.7mV    249.8mV    271mV
[Falling Waveform]
R_fixture= 50.000
V_fixture= 0.0
V_fixture_min= 0.0
V_fixture_max= 0.0
|time   V(typ)   V(min)   V(max)
0s        683.6mV    639.6mV    688.7mV
377ps     684.3mV    639.7mV    686.2mV
408ps     685.7mV    639.9mV    605.6mV
479ps     675.3mV    641.8mV    250.2mV
528ps     528.3mV    642.5mV    98.57mV
592ps     226.9mV    596.6mV    31.95mV
712ps     28.36mV    202.3mV    4.617mV
819ps     5.753mV    38.95mV    863uV
1.024ns   321.6uV    2.627mV    -25.91uV
10ns      1.134uV    6.173uV    523.1nV
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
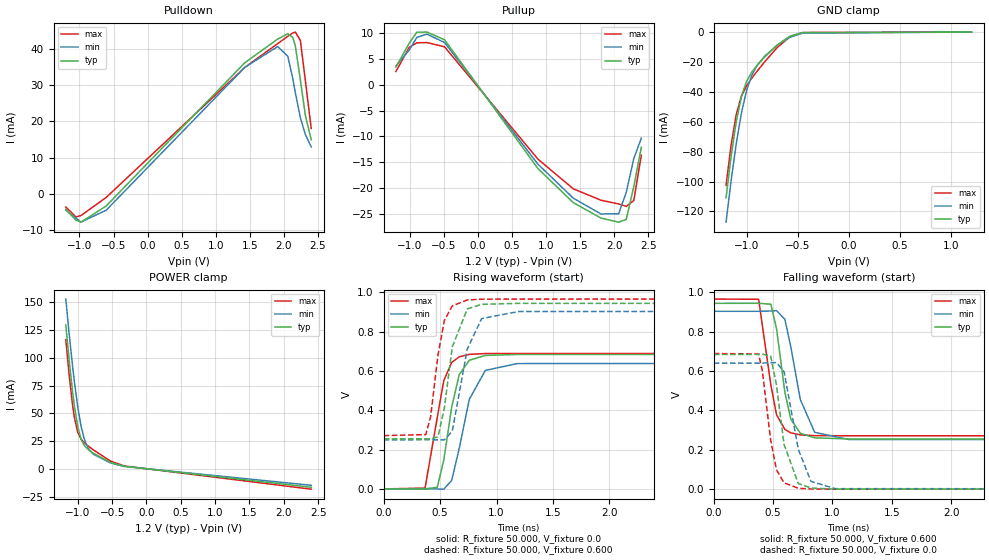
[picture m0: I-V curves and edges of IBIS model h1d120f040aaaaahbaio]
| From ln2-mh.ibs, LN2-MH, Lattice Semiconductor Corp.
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|   Model h1d120f040aaaaahbaio
[Model] h1d120f040aaaaahbaio
| Clamp models do not include dynamic input termination. Please refer to
| the h1d120axxxaaaaahbain model for input termination.
Model_type I/O
Polarity   Non-Inverting
Enable   Active-Low
Vinl =  0.500V
Vinh =  0.700V
Vmeas =  0.600V
Cref =  20.000pF
Rref =  50.000
Vref =  0.600V
C_comp   2.000pF   1.500pF   2.500pF
[Temperature Range]   25.000   0.125k   -40.000
[Voltage Range]   1.200V   1.160V   1.240V
[C Comp Corner]
C_comp   2.000pF   1.500pF   2.500pF
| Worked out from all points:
|   slope of the pulldown table from 0 to 0.18 V, typ, clamps not added: 49.1 ohm
|   slope of the pullup table from 0 to 0.18 V, typ, clamps not added: 50.7 ohm
|   GND clamp passes 1 mA (typ) near -0.51 V on its own axis
|   POWER clamp passes 1 mA (typ) near -0.14 V on its own axis
|   rising waveform, R_fixture 50.000, V_fixture 0.0: 20-80 % time 120ps typ, 148ps min, 110ps max; typ from 0 V to 0.684 V
|   rising waveform, R_fixture 50.000, V_fixture 0.600: 20-80 % time 104ps typ, 126ps min, 98.1ps max; typ from 0.255 V to 0.943 V
|   falling waveform, R_fixture 50.000, V_fixture 0.600: 20-80 % time 100ps typ, 128ps min, 92.7ps max; typ from 0.943 V to 0.255 V
|   falling waveform, R_fixture 50.000, V_fixture 0.0: 20-80 % time 96.8ps typ, 120ps min, 90.9ps max; typ from 0.684 V to 0 V
[Pulldown]
|Voltage   I(typ)   I(min)   I(max)
-1.2V     -4.163mA   -4.374mA   -3.519mA
-1.052V   -7.14mA    -6.587mA   -6.274mA
-978mV    -7.716mA   -7.673mA   -5.895mA
-608mV    -3.26mA    -4.431mA   -914.7uA
1.427V    36.18mA    34.91mA    34.89mA
1.908V    42.67mA    40.6mA     41.41mA
2.056V    44.13mA    37.94mA    43.43mA
2.13V     43.12mA    31.74mA    44.36mA
2.167V    40.82mA    27.89mA    44.59mA
2.241V    31.35mA    21.02mA    42.27mA
2.315V    21.58mA    16.37mA    31.05mA
2.4V      14.97mA    13.01mA    18.06mA
[Pullup]
|Voltage   I(typ)   I(min)   I(max)
-1.2V     3.457mA    3.655mA    2.592mA
-1.004V   8.086mA    6.755mA    7.274mA
-893mV    10.2mA     9.198mA    8.148mA
-745mV    10.22mA    9.811mA    8.193mA
-486mV    8.731mA    8.199mA    7.362mA
883mV     -16.21mA   -15.36mA   -14.39mA
1.401V    -22.81mA   -21.94mA   -20.13mA
1.808V    -25.8mA    -25.02mA   -22.35mA
2.067V    -26.6mA    -24.96mA   -23.06mA
2.178V    -26.07mA   -20.83mA   -23.54mA
2.289V    -19.7mA    -14.3mA    -22.4mA
2.4V      -12.06mA   -10.3mA    -13.61mA
[GND_clamp]
|Voltage   I(typ)   I(min)   I(max)
-1.2V     -110.8mA   -127.2mA   -102.6mA
-1.15V    -82.88mA   -99.17mA   -75.34mA
-1.1V     -59.79mA   -74.49mA   -54.99mA
-1.05V    -43.24mA   -54.27mA   -42.84mA
-1V       -33.11mA   -39.27mA   -36mA
-950mV    -26.96mA   -29.24mA   -31mA
-900mV    -22.5mA    -22.74mA   -26.51mA
-825mV    -16.83mA   -16.32mA   -20.1mA
-700mV    -8.63mA    -8.753mA   -10.36mA
-575mV    -2.733mA   -3.411mA   -3.145mA
-450mV    -330.4uA   -676.6uA   -311.8uA
1.2V      0A         0A         0A
[POWER_clamp]
|Voltage   I(typ)   I(min)   I(max)
-1.175V   129.6mA    153mA      116.4mA
-1.125V   97.27mA    121mA      83.9mA
-1.075V   68.82mA    91.78mA    56.85mA
-1.05V    56.65mA    78.49mA    46.38mA
-1V       37.7mA     55.32mA    32.72mA
-950mV    26.39mA    37.62mA    26.5mA
-900mV    20.64mA    25.77mA    23.22mA
-850mV    17.46mA    18.73mA    20.69mA
-775mV    14.15mA    13.23mA    17.2mA
-525mV    5.867mA    5.39mA     7.094mA
-325mV    2.369mA    2.214mA    2.634mA
2.4V      -16.54mA   -14.78mA   -18.27mA
[Ramp]
| variable   typ   min   max
dV/dt_r   0.410/0.120n   0.384/0.149n   0.413/0.110n
dV/dt_f   0.414/0.108n   0.397/0.142n   0.418/95.414p
R_load = 50.000
[Rising Waveform]
R_fixture= 50.000
V_fixture= 0.0
V_fixture_min= 0.0
V_fixture_max= 0.0
|time   V(typ)   V(min)   V(max)
0s        1.134uV    6.183uV    517.4nV
367ps     64.99uV    45.5uV     4.085mV
475ps     8.205mV    -325.3uV   362.8mV
533ps     147.2mV    -1.348mV   551.2mV
603ps     416.4mV    43.58mV    643mV
670ps     581.1mV    207.2mV    671.7mV
759ps     654mV      455.8mV    684mV
901ps     678.7mV    602.5mV    688.2mV
1.183ns   683.5mV    637.1mV    688.7mV
10ns      683.6mV    639.6mV    688.7mV
[Rising Waveform]
R_fixture= 50.000
V_fixture= 0.600
V_fixture_min= 0.583
V_fixture_max= 0.619
|time   V(typ)   V(min)   V(max)
0s        254.7mV    249.8mV    271mV
373ps     254.8mV    249.9mV    276mV
416ps     254.3mV    249.9mV    366.2mV
481ps     264.2mV    249.5mV    679.4mV
538ps     411.7mV    249.5mV    856.5mV
608ps     721.8mV    293.3mV    930.6mV
741ps     915.2mV    711.1mV    960.7mV
868ps     938.4mV    866mV      964.6mV
1.196ns   943.4mV    901.9mV    965.2mV
10ns      943.4mV    903.1mV    965.2mV
[Falling Waveform]
R_fixture= 50.000
V_fixture= 0.600
V_fixture_min= 0.583
V_fixture_max= 0.619
|time   V(typ)   V(min)   V(max)
0s        943.4mV    903.1mV    965.1mV
378ps     943.7mV    903.1mV    964mV
481ps     938.9mV    904.6mV    527.5mV
529ps     813.4mV    906.3mV    377.1mV
599ps     491.1mV    862mV      303.6mV
649ps     355.7mV    721.6mV    285.9mV
729ps     283.8mV    454.8mV    275.4mV
850ps     260.5mV    288.5mV    271.8mV
1.137ns   255mV      252.1mV    271mV
10ns      254.7mV    249.8mV    271mV
[Falling Waveform]
R_fixture= 50.000
V_fixture= 0.0
V_fixture_min= 0.0
V_fixture_max= 0.0
|time   V(typ)   V(min)   V(max)
0s        683.6mV    639.6mV    688.7mV
377ps     684.3mV    639.7mV    686.2mV
408ps     685.7mV    639.9mV    605.6mV
479ps     675.3mV    641.8mV    250.2mV
528ps     528.3mV    642.5mV    98.57mV
592ps     226.9mV    596.6mV    31.95mV
712ps     28.36mV    202.3mV    4.617mV
819ps     5.753mV    38.95mV    863uV
1.024ns   321.6uV    2.627mV    -25.91uV
10ns      1.134uV    6.173uV    523.1nV
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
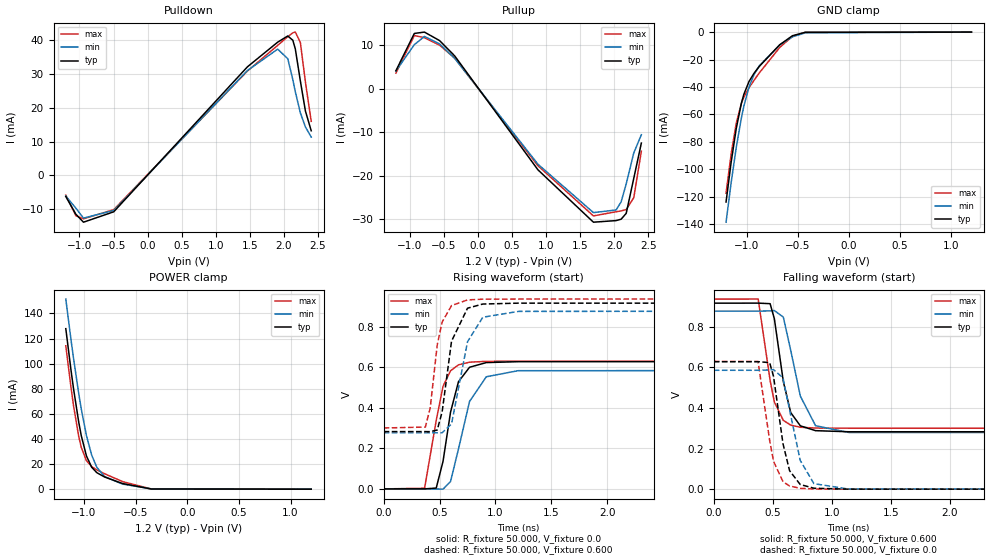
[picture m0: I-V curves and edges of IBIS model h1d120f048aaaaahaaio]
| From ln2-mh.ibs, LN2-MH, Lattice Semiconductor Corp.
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|   Model h1d120f048aaaaahaaio
[Model] h1d120f048aaaaahaaio
| Clamp models do not include dynamic input termination. Please refer to
| the h1d120axxxaaaaahaain model for input termination.
Model_type I/O
Polarity   Non-Inverting
Enable   Active-Low
Vinl =  0.500V
Vinh =  0.700V
Vmeas =  0.600V
Cref =  20.000pF
Rref =  50.000
Vref =  0.600V
C_comp   2.000pF   1.500pF   2.500pF
[Temperature Range]   25.000   0.125k   -40.000
[Voltage Range]   1.200V   1.160V   1.240V
[C Comp Corner]
C_comp   2.000pF   1.500pF   2.500pF
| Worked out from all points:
|   slope of the pulldown table from 0 to 0.18 V, typ, clamps not added: 44.5 ohm
|   slope of the pullup table from 0 to 0.18 V, typ, clamps not added: 44.9 ohm
|   GND clamp passes 1 mA (typ) near -0.49 V on its own axis
|   POWER clamp passes 1 mA (typ) near -0.45 V on its own axis
|   rising waveform, R_fixture 50.000, V_fixture 0.0: 20-80 % time 123ps typ, 155ps min, 110ps max; typ from 0 V to 0.627 V
|   rising waveform, R_fixture 50.000, V_fixture 0.600: 20-80 % time 103ps typ, 129ps min, 93.1ps max; typ from 0.282 V to 0.916 V
|   falling waveform, R_fixture 50.000, V_fixture 0.600: 20-80 % time 107ps typ, 138ps min, 96.7ps max; typ from 0.916 V to 0.282 V
|   falling waveform, R_fixture 50.000, V_fixture 0.0: 20-80 % time 103ps typ, 128ps min, 95.7ps max; typ from 0.627 V to 0 V
[Pulldown]
|Voltage   I(typ)   I(min)   I(max)
-1.2V     -6.256mA   -6.129mA   -5.843mA
-1.052V   -11.49mA   -9.695mA   -11.92mA
-941mV    -13.84mA   -12.63mA   -12.85mA
-497mV    -10.77mA   -10.38mA   -10.13mA
1.464V    32.07mA    30.98mA    30.83mA
1.908V    39.36mA    37.3mA     38.42mA
2.056V    41.19mA    34.47mA    40.98mA
2.13V     39.93mA    28.3mA     42.12mA
2.167V    37.33mA    24.67mA    42.34mA
2.241V    27.83mA    18.44mA    39.23mA
2.315V    18.99mA    14.3mA     27.54mA
2.4V      13.18mA    11.32mA    15.97mA
[Pullup]
|Voltage   I(typ)   I(min)   I(max)
-1.2V     4.095mA    4.031mA    3.539mA
-930mV    12.65mA    10.07mA    12.18mA
-782mV    12.96mA    11.96mA    11.66mA
-560mV    11.01mA    10.25mA    9.966mA
-338mV    7.489mA    6.936mA    6.974mA
883mV     -18.67mA   -17.38mA   -17.73mA
1.697V    -30.7mA    -28.5mA    -29.26mA
2.03V     -30.33mA   -27.89mA   -28.3mA
2.104V    -30.01mA   -26.01mA   -28.11mA
2.178V    -28.67mA   -21.9mA    -27.8mA
2.289V    -20.61mA   -14.78mA   -25.05mA
2.4V      -12.53mA   -10.62mA   -14.4mA
[GND_clamp]
|Voltage   I(typ)   I(min)   I(max)
-1.2V     -123.9mA   -138.6mA   -117.5mA
-1.15V    -94.78mA   -109.7mA   -88.79mA
-1.1V     -70.2mA    -84.05mA   -66.33mA
-1.05V    -51.82mA   -62.6mA    -51.98mA
-1.025V   -45.18mA   -53.76mA   -47.32mA
-975mV    -35.96mA   -40.02mA   -40.52mA
-925mV    -29.87mA   -30.81mA   -34.98mA
-875mV    -25.03mA   -24.57mA   -29.81mA
-675mV    -9.229mA   -9.412mA   -11.2mA
-550mV    -2.635mA   -3.442mA   -3.059mA
-425mV    -169.7uA   -547.4uA   -117uA
1.2V      0A         0A         0A
[POWER_clamp]
|Voltage   I(typ)   I(min)   I(max)
-1.175V   127.9mA    151.5mA    114.3mA
-1.125V   95.1mA     119.3mA    81.28mA
-1.1V     80mA       104.2mA    66.46mA
-1.05V    53.45mA    76.25mA    42.06mA
-1.025V   42.52mA    63.79mA    33.25mA
-975mV    26.42mA    42.64mA    22.65mA
-925mV    17.53mA    27.24mA    17.97mA
-875mV    13.15mA    17.46mA    15.37mA
-800mV    9.709mA    10.06mA    12.3mA
-625mV    4.479mA    4.015mA    6.021mA
-350mV    147.7uA    296.5uA    176.7uA
1.2V      0A         0A         0A
[Ramp]
| variable   typ   min   max
dV/dt_r   0.376/0.123n   0.351/0.155n   0.378/0.110n
dV/dt_f   0.380/0.115n   0.365/0.155n   0.383/98.058p
R_load = 50.000
[Rising Waveform]
R_fixture= 50.000
V_fixture= 0.0
V_fixture_min= 0.0
V_fixture_max= 0.0
|time   V(typ)   V(min)   V(max)
0s        1.282uV    6.961uV    584.4nV
366ps     73.43uV    52.02uV    3.138mV
470ps     4.129mV    -247.3uV   337.1mV
531ps     136mV      -1.348mV   505.8mV
598ps     378.3mV    36.02mV    582.3mV
669ps     528.4mV    196.9mV    611.7mV
768ps     599.8mV    431.2mV    624.8mV
918ps     622.8mV    552.9mV    628.9mV
1.202ns   627.2mV    582.8mV    629.4mV
10ns      627.3mV    585.3mV    629.4mV
[Rising Waveform]
R_fixture= 50.000
V_fixture= 0.600
V_fixture_min= 0.583
V_fixture_max= 0.619
|time   V(typ)   V(min)   V(max)
0s        282.5mV    276.8mV    300.3mV
373ps     282.5mV    276.9mV    304.8mV
416ps     282.1mV    276.9mV    398mV
479ps     290.2mV    276.5mV    709.3mV
523ps     379.7mV    276.8mV    822.8mV
607ps     728.4mV    320.2mV    903.9mV
750ps     891mV      725.5mV    931.8mV
887ps     911.5mV    846.5mV    935.5mV
1.207ns   915.9mV    875.3mV    936mV
10ns      915.9mV    876.6mV    936mV
[Falling Waveform]
R_fixture= 50.000
V_fixture= 0.600
V_fixture_min= 0.583
V_fixture_max= 0.619
|time   V(typ)   V(min)   V(max)
0s        915.9mV    876.6mV    936mV
376ps     916.1mV    876.6mV    936.1mV
477ps     913.3mV    877.9mV    535.6mV
513ps     839.3mV    879.5mV    429mV
589ps     529.6mV    847.1mV    338.5mV
652ps     376.6mV    682.4mV    315.2mV
733ps     311.8mV    458.1mV    304.8mV
862ps     288mV      312.4mV    300.9mV
1.143ns   282.6mV    279.1mV    300.2mV
10ns      282.5mV    276.8mV    300.3mV
[Falling Waveform]
R_fixture= 50.000
V_fixture= 0.0
V_fixture_min= 0.0
V_fixture_max= 0.0
|time   V(typ)   V(min)   V(max)
0s        627.3mV    585.3mV    629.4mV
375ps     627.9mV    585.3mV    628.1mV
473ps     623.1mV    587.2mV    240.8mV
506ps     555.1mV    588.4mV    137.2mV
586ps     223.9mV    548.6mV    36.78mV
642ps     90.85mV    389.8mV    15.58mV
732ps     22.84mV    141.6mV    4.109mV
848ps     4.588mV    27.17mV    716.6uV
1.138ns   33.01uV    878.6uV    -59.45uV
10ns      1.284uV    6.953uV    591.8nV
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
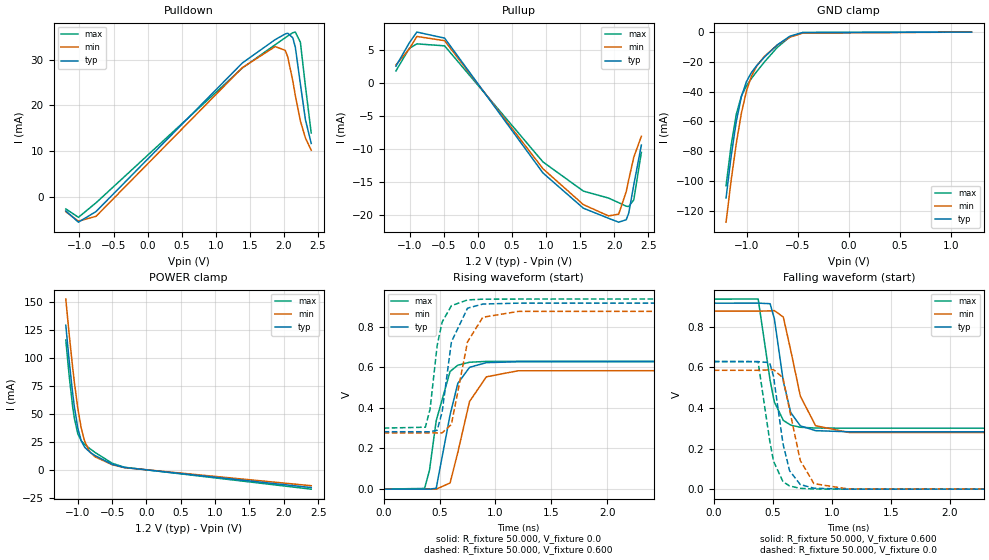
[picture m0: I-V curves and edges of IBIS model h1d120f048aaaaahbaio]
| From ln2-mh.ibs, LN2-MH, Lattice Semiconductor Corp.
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|   Model h1d120f048aaaaahbaio
[Model] h1d120f048aaaaahbaio
| Clamp models do not include dynamic input termination. Please refer to
| the h1d120axxxaaaaahbain model for input termination.
Model_type I/O
Polarity   Non-Inverting
Enable   Active-Low
Vinl =  0.500V
Vinh =  0.700V
Vmeas =  0.600V
Cref =  20.000pF
Rref =  50.000
Vref =  0.600V
C_comp   2.000pF   1.500pF   2.500pF
[Temperature Range]   25.000   0.125k   -40.000
[Voltage Range]   1.200V   1.160V   1.240V
[C Comp Corner]
C_comp   2.000pF   1.500pF   2.500pF
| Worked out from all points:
|   slope of the pulldown table from 0 to 0.18 V, typ, clamps not added: 62.2 ohm
|   slope of the pullup table from 0 to 0.18 V, typ, clamps not added: 64.3 ohm
|   GND clamp passes 1 mA (typ) near -0.51 V on its own axis
|   POWER clamp passes 1 mA (typ) near -0.15 V on its own axis
|   rising waveform, R_fixture 50.000, V_fixture 0.0: 20-80 % time 123ps typ, 155ps min, 110ps max; typ from 0 V to 0.627 V
|   rising waveform, R_fixture 50.000, V_fixture 0.600: 20-80 % time 103ps typ, 129ps min, 93.1ps max; typ from 0.282 V to 0.916 V
|   falling waveform, R_fixture 50.000, V_fixture 0.600: 20-80 % time 107ps typ, 138ps min, 96.7ps max; typ from 0.916 V to 0.282 V
|   falling waveform, R_fixture 50.000, V_fixture 0.0: 20-80 % time 103ps typ, 128ps min, 95.7ps max; typ from 0.627 V to 0 V
[Pulldown]
|Voltage   I(typ)   I(min)   I(max)
-1.2V     -3.083mA   -3.26mA    -2.647mA
-1.015V   -5.553mA   -5.326mA   -4.485mA
-756mV    -3.214mA   -4.262mA   -1.306mA
1.39V     29.29mA    28.26mA    28.19mA
1.871V    34.39mA    32.87mA    33.27mA
2.019V    35.64mA    32.05mA    34.81mA
2.056V    35.79mA    30.59mA    35.2mA
2.13V     34.78mA    25.32mA    35.9mA
2.167V    32.71mA    22.14mA    36.04mA
2.241V    24.68mA    16.59mA    33.81mA
2.315V    16.86mA    12.87mA    24.17mA
2.4V      11.68mA    10.18mA    13.97mA
[Pullup]
|Voltage   I(typ)   I(min)   I(max)
-1.2V     2.587mA    2.779mA    1.867mA
-1.004V   6.121mA    5.197mA    5.297mA
-893mV    7.751mA    7.093mA    5.968mA
-486mV    6.842mA    6.45mA     5.668mA
957mV     -13.58mA   -12.94mA   -11.91mA
1.549V    -18.91mA   -18.37mA   -16.32mA
1.919V    -20.44mA   -20.08mA   -17.38mA
2.067V    -21.03mA   -19.82mA   -18.07mA
2.178V    -20.66mA   -16.41mA   -18.61mA
2.215V    -19.66mA   -14.59mA   -18.66mA
2.289V    -15.38mA   -11.19mA   -17.64mA
2.4V      -9.36mA    -8.027mA   -10.47mA
[GND_clamp]
|Voltage   I(typ)   I(min)   I(max)
-1.2V     -111.3mA   -127.6mA   -103.1mA
-1.15V    -83.23mA   -99.5mA    -75.78mA
-1.1V     -60.04mA   -74.76mA   -55.21mA
-1.05V    -43.36mA   -54.45mA   -42.88mA
-1V       -33.14mA   -39.38mA   -35.97mA
-950mV    -26.95mA   -29.29mA   -30.97mA
-900mV    -22.48mA   -22.75mA   -26.47mA
-825mV    -16.81mA   -16.32mA   -20.08mA
-700mV    -8.623mA   -8.752mA   -10.35mA
-575mV    -2.726mA   -3.413mA   -3.134mA
-450mV    -321.1uA   -678uA     -290uA
1.2V      0A         0A         0A
[POWER_clamp]
|Voltage   I(typ)   I(min)   I(max)
-1.175V   129.5mA    152.9mA    116.2mA
-1.125V   97.13mA    120.9mA    83.71mA
-1.075V   68.64mA    91.65mA    56.62mA
-1.05V    56.45mA    78.35mA    46.09mA
-1V       37.45mA    55.15mA    32.35mA
-950mV    26.11mA    37.43mA    26.09mA
-900mV    20.34mA    25.56mA    22.82mA
-825mV    15.97mA    16.2mA     19.12mA
-750mV    12.93mA    11.84mA    15.73mA
-500mV    5.062mA    4.712mA    6.053mA
-325mV    2.253mA    2.118mA    2.479mA
2.4V      -15.72mA   -14.07mA   -17.16mA
[Ramp]
| variable   typ   min   max
dV/dt_r   0.376/0.123n   0.351/0.155n   0.378/0.110n
dV/dt_f   0.380/0.115n   0.365/0.155n   0.383/98.058p
R_load = 50.000
[Rising Waveform]
R_fixture= 50.000
V_fixture= 0.0
V_fixture_min= 0.0
V_fixture_max= 0.0
|time   V(typ)   V(min)   V(max)
0s        1.282uV    6.961uV    584.4nV
366ps     73.37uV    52.02uV    3.139mV
410ps     -425.6uV   73.75uV    93.35mV
470ps     4.154mV    -247.3uV   337.1mV
594ps     365.6mV    30.12mV    579.5mV
663ps     520.4mV    180.2mV    610.2mV
768ps     599.8mV    431.2mV    624.8mV
918ps     622.8mV    552.9mV    628.9mV
1.202ns   627.2mV    582.8mV    629.4mV
10ns      627.4mV    585.3mV    629.4mV
[Rising Waveform]
R_fixture= 50.000
V_fixture= 0.600
V_fixture_min= 0.583
V_fixture_max= 0.619
|time   V(typ)   V(min)   V(max)
0s        282.5mV    276.8mV    300.3mV
373ps     282.5mV    276.9mV    304.8mV
415ps     282.1mV    276.9mV    394mV
479ps     290.1mV    276.5mV    709.3mV
523ps     379.8mV    276.8mV    822.8mV
606ps     725.5mV    318.6mV    903.4mV
750ps     891mV      725.5mV    931.8mV
887ps     911.5mV    846.5mV    935.5mV
1.207ns   915.9mV    875.3mV    936mV
10ns      915.9mV    876.6mV    936mV
[Falling Waveform]
R_fixture= 50.000
V_fixture= 0.600
V_fixture_min= 0.583
V_fixture_max= 0.619
|time   V(typ)   V(min)   V(max)
0s        915.9mV    876.6mV    936mV
376ps     916.1mV    876.6mV    936.1mV
477ps     913.3mV    877.9mV    535.6mV
513ps     839.3mV    879.5mV    429mV
589ps     529.6mV    847.1mV    338.5mV
652ps     376.6mV    682.4mV    315.2mV
733ps     311.8mV    458.1mV    304.8mV
862ps     288mV      312.4mV    300.9mV
1.143ns   282.6mV    279.1mV    300.2mV
10ns      282.5mV    276.8mV    300.3mV
[Falling Waveform]
R_fixture= 50.000
V_fixture= 0.0
V_fixture_min= 0.0
V_fixture_max= 0.0
|time   V(typ)   V(min)   V(max)
0s        627.3mV    585.3mV    629.4mV
375ps     627.9mV    585.3mV    628.1mV
473ps     623.1mV    587.2mV    240.8mV
506ps     555.1mV    588.4mV    137.2mV
586ps     223.9mV    548.6mV    36.78mV
642ps     90.85mV    389.8mV    15.58mV
732ps     22.84mV    141.6mV    4.109mV
848ps     4.588mV    27.17mV    716.6uV
1.138ns   33.01uV    878.6uV    -59.45uV
10ns      1.284uV    6.953uV    591.8nV
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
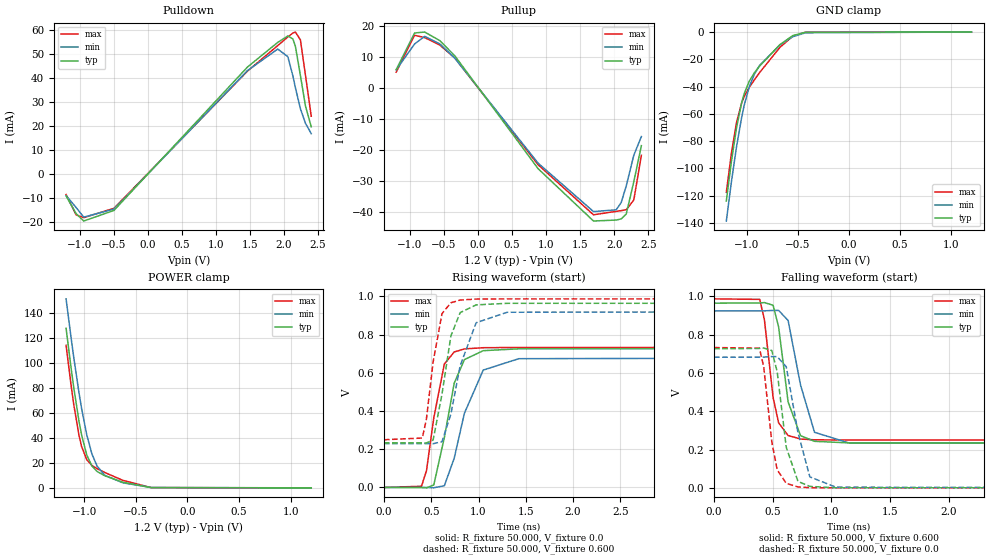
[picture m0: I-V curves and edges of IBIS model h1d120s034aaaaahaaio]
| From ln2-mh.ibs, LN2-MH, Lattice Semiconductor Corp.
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|   Model h1d120s034aaaaahaaio
[Model] h1d120s034aaaaahaaio
| Clamp models do not include dynamic input termination. Please refer to
| the h1d120axxxaaaaahaain model for input termination.
Model_type I/O
Polarity   Non-Inverting
Enable   Active-Low
Vinl =  0.500V
Vinh =  0.700V
Vmeas =  0.600V
Cref =  20.000pF
Rref =  50.000
Vref =  0.600V
C_comp   2.000pF   1.500pF   2.500pF
[Temperature Range]   25.000   0.125k   -40.000
[Voltage Range]   1.200V   1.160V   1.240V
[C Comp Corner]
C_comp   2.000pF   1.500pF   2.500pF
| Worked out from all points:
|   slope of the pulldown table from 0 to 0.18 V, typ, clamps not added: 31.9 ohm
|   slope of the pullup table from 0 to 0.18 V, typ, clamps not added: 32.3 ohm
|   GND clamp passes 1 mA (typ) near -0.49 V on its own axis
|   POWER clamp passes 1 mA (typ) near -0.45 V on its own axis
|   rising waveform, R_fixture 50.000, V_fixture 0.0: 20-80 % time 163ps typ, 221ps min, 131ps max; typ from 0 V to 0.727 V
|   rising waveform, R_fixture 50.000, V_fixture 0.600: 20-80 % time 139ps typ, 186ps min, 113ps max; typ from 0.234 V to 0.965 V
|   falling waveform, R_fixture 50.000, V_fixture 0.600: 20-80 % time 97.4ps typ, 126ps min, 87ps max; typ from 0.965 V to 0.234 V
|   falling waveform, R_fixture 50.000, V_fixture 0.0: 20-80 % time 91.3ps typ, 115ps min, 83.8ps max; typ from 0.726 V to 0 V
[Pulldown]
|Voltage   I(typ)   I(min)   I(max)
-1.2V     -9.028mA   -8.849mA   -8.433mA
-1.052V   -16.37mA   -13.85mA   -16.9mA
-941mV    -19.44mA   -17.82mA   -18.04mA
-497mV    -15.03mA   -14.49mA   -14.16mA
1.464V    44.67mA    43.19mA    42.97mA
1.908V    54.92mA    52.15mA    53.6mA
2.056V    57.61mA    48.99mA    57.18mA
2.13V     56.38mA    41.05mA    58.81mA
2.167V    53.35mA    36.11mA    59.24mA
2.241V    41.15mA    27.29mA    55.97mA
2.315V    28.48mA    21.26mA    41.29mA
2.4V      19.77mA    16.93mA    24.21mA
[Pullup]
|Voltage   I(typ)   I(min)   I(max)
-1.2V     6.003mA    5.923mA    5.177mA
-930mV    17.83mA    14.28mA    17.11mA
-782mV    18.14mA    16.75mA    16.33mA
-560mV    15.37mA    14.31mA    13.94mA
-338mV    10.42mA    9.655mA    9.718mA
883mV     -26mA      -24.21mA   -24.72mA
1.697V    -42.92mA   -39.87mA   -40.92mA
2.03V     -42.61mA   -39.3mA    -39.79mA
2.104V    -42.24mA   -36.95mA   -39.57mA
2.178V    -40.66mA   -31.58mA   -39.26mA
2.289V    -30.22mA   -21.65mA   -36.13mA
2.4V      -18.57mA   -15.64mA   -21.69mA
[GND_clamp]
|Voltage   I(typ)   I(min)   I(max)
-1.2V     -123.9mA   -138.6mA   -117.5mA
-1.15V    -94.79mA   -109.7mA   -88.79mA
-1.1V     -70.21mA   -84.06mA   -66.34mA
-1.05V    -51.83mA   -62.6mA    -51.99mA
-1.025V   -45.19mA   -53.76mA   -47.33mA
-975mV    -35.96mA   -40.02mA   -40.53mA
-925mV    -29.87mA   -30.82mA   -34.98mA
-875mV    -25.03mA   -24.57mA   -29.81mA
-675mV    -9.23mA    -9.413mA   -11.2mA
-550mV    -2.635mA   -3.443mA   -3.06mA
-425mV    -169.7uA   -547.4uA   -117uA
1.2V      0A         0A         0A
[POWER_clamp]
|Voltage   I(typ)   I(min)   I(max)
-1.175V   127.9mA    151.5mA    114.3mA
-1.125V   95.1mA     119.3mA    81.28mA
-1.1V     80mA       104.2mA    66.46mA
-1.05V    53.45mA    76.25mA    42.06mA
-1.025V   42.52mA    63.79mA    33.25mA
-975mV    26.42mA    42.64mA    22.65mA
-925mV    17.53mA    27.24mA    17.97mA
-875mV    13.15mA    17.46mA    15.37mA
-800mV    9.709mA    10.06mA    12.3mA
-625mV    4.479mA    4.015mA    6.021mA
-350mV    147.7uA    296.5uA    176.7uA
1.2V      0A         0A         0A
[Ramp]
| variable   typ   min   max
dV/dt_r   0.436/0.163n   0.409/0.221n   0.440/0.131n
dV/dt_f   0.439/0.109n   0.421/0.146n   0.444/92.562p
R_load = 50.000
[Rising Waveform]
R_fixture= 50.000
V_fixture= 0.0
V_fixture_min= 0.0
V_fixture_max= 0.0
|time   V(typ)   V(min)   V(max)
0s        1.021uV    5.586uV    466.9nV
397ps     -260uV     63.48uV    6.404mV
450ps     -1.991mV   -7.812uV   87.99mV
527ps     13.14mV    -1.615mV   364.1mV
639ps     261.9mV    9.27mV     646.3mV
743ps     545.8mV    153.1mV    709.1mV
851ps     669.1mV    388.6mV    725.1mV
1.05ns    715.8mV    614.3mV    731.3mV
1.426ns   725.5mV    673.9mV    732.6mV
10ns      726.5mV    682.1mV    732.6mV
[Rising Waveform]
R_fixture= 50.000
V_fixture= 0.600
V_fixture_min= 0.583
V_fixture_max= 0.619
|time   V(typ)   V(min)   V(max)
0s        233.9mV    229.5mV    249.7mV
406ps     233.5mV    229.6mV    258.7mV
449ps     233mV      229.5mV    357.4mV
520ps     247.9mV    228.9mV    656.6mV
614ps     488.7mV    239.6mV    909.7mV
708ps     793.3mV    384.2mV    966.6mV
806ps     915mV      636.9mV    980.8mV
975ps     955.4mV    862mV      985.8mV
1.303ns   963.6mV    916.8mV    986.8mV
10ns      964.5mV    923.8mV    986.9mV
[Falling Waveform]
R_fixture= 50.000
V_fixture= 0.600
V_fixture_min= 0.583
V_fixture_max= 0.619
|time   V(typ)   V(min)   V(max)
0s        964.5mV    923.8mV    986.9mV
389ps     965.4mV    924mV      984.2mV
429ps     967.5mV    924.3mV    877.9mV
503ps     953.6mV    926.6mV    471.6mV
550ps     840.3mV    926.6mV    339.5mV
631ps     448.6mV    874mV      273.3mV
737ps     272.4mV    536.6mV    254.8mV
856ps     243mV      290.1mV    250.8mV
1.149ns   234.7mV    234.5mV    249.7mV
10ns      233.9mV    229.5mV    249.7mV
[Falling Waveform]
R_fixture= 50.000
V_fixture= 0.0
V_fixture_min= 0.0
V_fixture_max= 0.0
|time   V(typ)   V(min)   V(max)
0s        726.5mV    682.1mV    732.6mV
386ps     728mV      682.3mV    729.7mV
423ps     730.1mV    682.8mV    632.3mV
492ps     717.1mV    685.6mV    239.7mV
538ps     605.5mV    685.2mV    93.86mV
615ps     212mV      632.3mV    23.49mV
715ps     33.62mV    288.7mV    4.69mV
816ps     7.551mV    57.14mV    1.01mV
1.039ns   474.5uV    3.284mV    -5.333uV
10ns      1.02uV     5.574uV    471.9nV
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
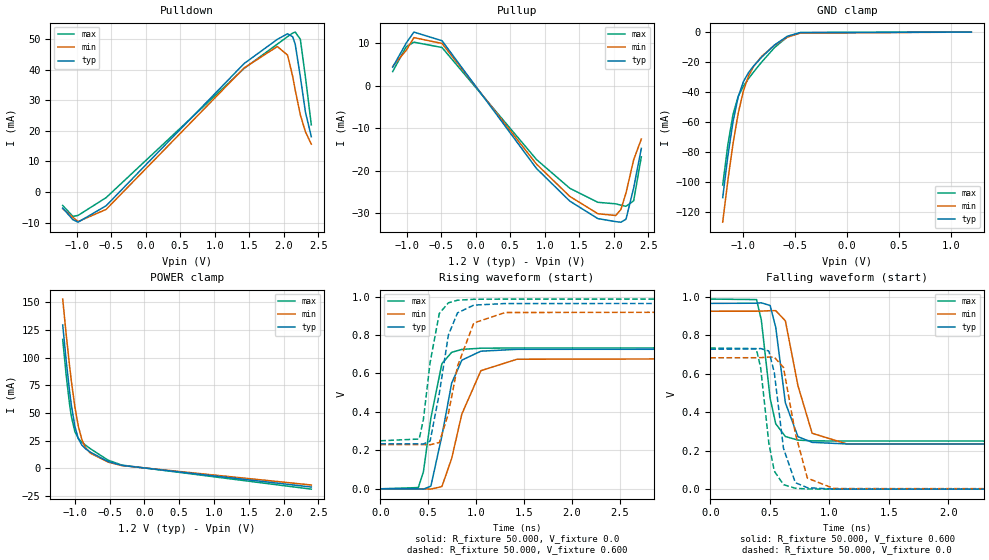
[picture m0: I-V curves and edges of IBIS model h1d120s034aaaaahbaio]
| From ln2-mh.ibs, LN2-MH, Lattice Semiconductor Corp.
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|   Model h1d120s034aaaaahbaio
[Model] h1d120s034aaaaahbaio
| Clamp models do not include dynamic input termination. Please refer to
| the h1d120axxxaaaaahbain model for input termination.
Model_type I/O
Polarity   Non-Inverting
Enable   Active-Low
Vinl =  0.500V
Vinh =  0.700V
Vmeas =  0.600V
Cref =  20.000pF
Rref =  50.000
Vref =  0.600V
C_comp   2.000pF   1.500pF   2.500pF
[Temperature Range]   25.000   0.125k   -40.000
[Voltage Range]   1.200V   1.160V   1.240V
[C Comp Corner]
C_comp   2.000pF   1.500pF   2.500pF
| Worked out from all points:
|   slope of the pulldown table from 0 to 0.18 V, typ, clamps not added: 41.2 ohm
|   slope of the pullup table from 0 to 0.18 V, typ, clamps not added: 42.3 ohm
|   GND clamp passes 1 mA (typ) near -0.51 V on its own axis
|   POWER clamp passes 1 mA (typ) near -0.14 V on its own axis
|   rising waveform, R_fixture 50.000, V_fixture 0.0: 20-80 % time 163ps typ, 221ps min, 131ps max; typ from 0 V to 0.727 V
|   rising waveform, R_fixture 50.000, V_fixture 0.600: 20-80 % time 139ps typ, 186ps min, 113ps max; typ from 0.234 V to 0.965 V
|   falling waveform, R_fixture 50.000, V_fixture 0.600: 20-80 % time 97.4ps typ, 126ps min, 87ps max; typ from 0.965 V to 0.234 V
|   falling waveform, R_fixture 50.000, V_fixture 0.0: 20-80 % time 91.3ps typ, 115ps min, 83.8ps max; typ from 0.726 V to 0 V
[Pulldown]
|Voltage   I(typ)   I(min)   I(max)
-1.2V     -5.234mA   -5.457mA   -4.39mA
-1.052V   -9.026mA   -8.255mA   -7.934mA
-978mV    -9.838mA   -9.643mA   -7.631mA
-571mV    -4.469mA   -5.658mA   -1.811mA
1.427V    41.96mA    40.53mA    40.36mA
1.908V    49.86mA    47.51mA    48.3mA
2.056V    51.69mA    44.73mA    50.75mA
2.13V     50.72mA    37.75mA    51.9mA
2.167V    48.26mA    33.3mA     52.23mA
2.241V    37.64mA    25.21mA    49.9mA
2.315V    26.09mA    19.65mA    37.49mA
2.4V      18.06mA    15.64mA    21.94mA
[Pullup]
|Voltage   I(typ)   I(min)   I(max)
-1.2V     4.297mA    4.507mA    3.288mA
-1.004V   9.99mA     8.279mA    9.131mA
-893mV    12.55mA    11.25mA    10.18mA
-486mV    10.52mA    9.881mA    8.929mA
883mV     -19.5mA    -18.47mA   -17.39mA
1.364V    -27.13mA   -26.03mA   -24.12mA
1.771V    -31.25mA   -30.1mA    -27.42mA
2.03V     -31.96mA   -30.52mA   -27.78mA
2.104V    -32.09mA   -29.11mA   -28.09mA
2.178V    -31.4mA    -25.24mA   -28.36mA
2.289V    -24.05mA   -17.44mA   -27.07mA
2.4V      -14.77mA   -12.57mA   -16.75mA
[GND_clamp]
|Voltage   I(typ)   I(min)   I(max)
-1.2V     -110.5mA   -126.9mA   -102.1mA
-1.15V    -82.61mA   -98.92mA   -75.02mA
-1.1V     -59.6mA    -74.29mA   -54.81mA
-1.05V    -43.14mA   -54.12mA   -42.79mA
-1V       -33.07mA   -39.19mA   -36mA
-950mV    -26.96mA   -29.2mA    -31.01mA
-900mV    -22.5mA    -22.72mA   -26.51mA
-825mV    -16.83mA   -16.31mA   -20.09mA
-700mV    -8.624mA   -8.747mA   -10.35mA
-575mV    -2.729mA   -3.404mA   -3.138mA
-450mV    -329.9uA   -671.5uA   -314.7uA
1.2V      0A         0A         0A
[POWER_clamp]
|Voltage   I(typ)   I(min)   I(max)
-1.175V   129.7mA    153.1mA    116.5mA
-1.125V   97.38mA    121.1mA    84.03mA
-1.075V   68.95mA    91.87mA    57.04mA
-1.05V    56.8mA     78.59mA    46.6mA
-1V       37.88mA    55.44mA    33mA
-950mV    26.6mA     37.77mA    26.8mA
-900mV    20.86mA    25.93mA    23.51mA
-850mV    17.67mA    18.89mA    20.97mA
-775mV    14.35mA    13.39mA    17.46mA
-525mV    6.002mA    5.504mA    7.27mA
-325mV    2.453mA    2.285mA    2.745mA
2.4V      -17.13mA   -15.3mA    -19.07mA
[Ramp]
| variable   typ   min   max
dV/dt_r   0.436/0.163n   0.409/0.221n   0.440/0.131n
dV/dt_f   0.439/0.109n   0.421/0.146n   0.444/92.562p
R_load = 50.000
[Rising Waveform]
R_fixture= 50.000
V_fixture= 0.0
V_fixture_min= 0.0
V_fixture_max= 0.0
|time   V(typ)   V(min)   V(max)
0s        1.021uV    5.586uV    466.9nV
397ps     -259.7uV   63.48uV    6.405mV
450ps     -1.991mV   -7.806uV   87.99mV
528ps     13.92mV    -1.663mV   368mV
643ps     274.8mV    11.49mV    650.9mV
745ps     549.7mV    157.4mV    709.7mV
851ps     669.1mV    388.6mV    725.1mV
1.05ns    715.8mV    614.3mV    731.3mV
1.427ns   725.5mV    673.9mV    732.6mV
10ns      726.5mV    682.1mV    732.6mV
[Rising Waveform]
R_fixture= 50.000
V_fixture= 0.600
V_fixture_min= 0.583
V_fixture_max= 0.619
|time   V(typ)   V(min)   V(max)
0s        233.9mV    229.5mV    249.7mV
406ps     233.5mV    229.6mV    258.7mV
450ps     233mV      229.5mV    360.9mV
520ps     247.9mV    228.9mV    656.6mV
616ps     495.9mV    240.6mV    912.1mV
711ps     800mV      391.2mV    967.4mV
806ps     915mV      636.9mV    980.8mV
976ps     955.4mV    862.6mV    985.8mV
1.303ns   963.6mV    916.8mV    986.8mV
10ns      964.5mV    923.8mV    986.9mV
[Falling Waveform]
R_fixture= 50.000
V_fixture= 0.600
V_fixture_min= 0.583
V_fixture_max= 0.619
|time   V(typ)   V(min)   V(max)
0s        964.5mV    923.8mV    986.9mV
389ps     965.4mV    924mV      984.2mV
429ps     967.5mV    924.3mV    877.9mV
503ps     953.6mV    926.6mV    471.6mV
550ps     840.3mV    926.6mV    339.5mV
631ps     448.6mV    874mV      273.3mV
737ps     272.4mV    536.6mV    254.8mV
856ps     243mV      290.1mV    250.8mV
1.149ns   234.7mV    234.5mV    249.7mV
10ns      233.9mV    229.5mV    249.7mV
[Falling Waveform]
R_fixture= 50.000
V_fixture= 0.0
V_fixture_min= 0.0
V_fixture_max= 0.0
|time   V(typ)   V(min)   V(max)
0s        726.5mV    682.1mV    732.6mV
386ps     728mV      682.3mV    729.7mV
423ps     730.1mV    682.8mV    632.3mV
492ps     717.1mV    685.6mV    239.7mV
538ps     605.5mV    685.2mV    93.86mV
615ps     212mV      632.3mV    23.49mV
715ps     33.62mV    288.7mV    4.69mV
816ps     7.551mV    57.14mV    1.01mV
1.039ns   474.6uV    3.284mV    -5.333uV
10ns      1.02uV     5.574uV    471.9nV
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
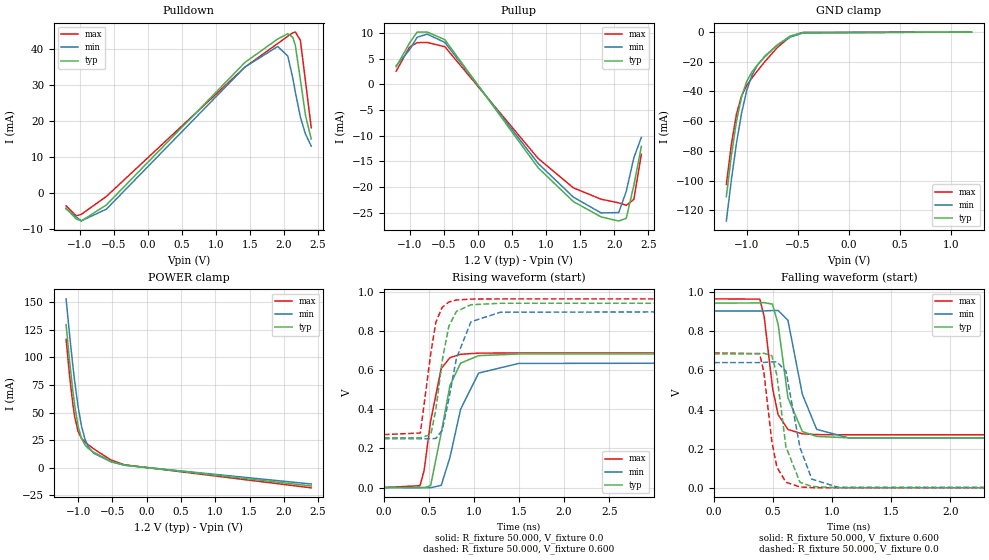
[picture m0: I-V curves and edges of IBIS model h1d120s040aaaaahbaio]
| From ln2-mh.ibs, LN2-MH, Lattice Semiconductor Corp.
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|   Model h1d120s040aaaaahbaio
[Model] h1d120s040aaaaahbaio
| Clamp models do not include dynamic input termination. Please refer to
| the h1d120axxxaaaaahbain model for input termination.
Model_type I/O
Polarity   Non-Inverting
Enable   Active-Low
Vinl =  0.500V
Vinh =  0.700V
Vmeas =  0.600V
Cref =  20.000pF
Rref =  50.000
Vref =  0.600V
C_comp   2.000pF   1.500pF   2.500pF
[Temperature Range]   25.000   0.125k   -40.000
[Voltage Range]   1.200V   1.160V   1.240V
[C Comp Corner]
C_comp   2.000pF   1.500pF   2.500pF
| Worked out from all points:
|   slope of the pulldown table from 0 to 0.18 V, typ, clamps not added: 49.1 ohm
|   slope of the pullup table from 0 to 0.18 V, typ, clamps not added: 50.7 ohm
|   GND clamp passes 1 mA (typ) near -0.51 V on its own axis
|   POWER clamp passes 1 mA (typ) near -0.14 V on its own axis
|   rising waveform, R_fixture 50.000, V_fixture 0.0: 20-80 % time 159ps typ, 214ps min, 132ps max; typ from 0 V to 0.684 V
|   rising waveform, R_fixture 50.000, V_fixture 0.600: 20-80 % time 134ps typ, 179ps min, 111ps max; typ from 0.255 V to 0.943 V
|   falling waveform, R_fixture 50.000, V_fixture 0.600: 20-80 % time 99.7ps typ, 129ps min, 89.9ps max; typ from 0.943 V to 0.255 V
|   falling waveform, R_fixture 50.000, V_fixture 0.0: 20-80 % time 93.9ps typ, 117ps min, 87.7ps max; typ from 0.684 V to 0 V
[Pulldown]
|Voltage   I(typ)   I(min)   I(max)
-1.2V     -4.163mA   -4.374mA   -3.519mA
-1.052V   -7.14mA    -6.587mA   -6.274mA
-978mV    -7.716mA   -7.673mA   -5.895mA
-608mV    -3.26mA    -4.431mA   -914.7uA
1.427V    36.18mA    34.91mA    34.89mA
1.908V    42.67mA    40.6mA     41.41mA
2.056V    44.13mA    37.94mA    43.43mA
2.13V     43.12mA    31.74mA    44.36mA
2.167V    40.82mA    27.89mA    44.59mA
2.241V    31.35mA    21.02mA    42.27mA
2.315V    21.58mA    16.37mA    31.05mA
2.4V      14.97mA    13.01mA    18.06mA
[Pullup]
|Voltage   I(typ)   I(min)   I(max)
-1.2V     3.457mA    3.655mA    2.592mA
-1.004V   8.086mA    6.755mA    7.274mA
-893mV    10.2mA     9.198mA    8.148mA
-745mV    10.22mA    9.81mA     8.193mA
-486mV    8.731mA    8.199mA    7.362mA
883mV     -16.21mA   -15.36mA   -14.39mA
1.401V    -22.81mA   -21.94mA   -20.13mA
1.808V    -25.8mA    -25.02mA   -22.35mA
2.067V    -26.6mA    -24.96mA   -23.06mA
2.178V    -26.07mA   -20.83mA   -23.54mA
2.289V    -19.7mA    -14.3mA    -22.4mA
2.4V      -12.06mA   -10.3mA    -13.61mA
[GND_clamp]
|Voltage   I(typ)   I(min)   I(max)
-1.2V     -110.8mA   -127.2mA   -102.6mA
-1.15V    -82.88mA   -99.17mA   -75.34mA
-1.1V     -59.79mA   -74.49mA   -54.99mA
-1.05V    -43.24mA   -54.27mA   -42.84mA
-1V       -33.11mA   -39.27mA   -36mA
-950mV    -26.96mA   -29.24mA   -31mA
-900mV    -22.5mA    -22.74mA   -26.51mA
-825mV    -16.83mA   -16.32mA   -20.1mA
-700mV    -8.63mA    -8.753mA   -10.36mA
-575mV    -2.733mA   -3.411mA   -3.145mA
-450mV    -330.4uA   -676.6uA   -311.8uA
1.2V      0A         0A         0A
[POWER_clamp]
|Voltage   I(typ)   I(min)   I(max)
-1.175V   129.6mA    153mA      116.4mA
-1.125V   97.27mA    121mA      83.9mA
-1.075V   68.82mA    91.78mA    56.85mA
-1.05V    56.65mA    78.49mA    46.38mA
-1V       37.7mA     55.32mA    32.72mA
-950mV    26.39mA    37.62mA    26.5mA
-900mV    20.64mA    25.77mA    23.22mA
-850mV    17.46mA    18.73mA    20.69mA
-775mV    14.15mA    13.23mA    17.2mA
-525mV    5.867mA    5.39mA     7.094mA
-325mV    2.369mA    2.214mA    2.634mA
2.4V      -16.54mA   -14.78mA   -18.27mA
[Ramp]
| variable   typ   min   max
dV/dt_r   0.410/0.160n   0.384/0.214n   0.413/0.132n
dV/dt_f   0.414/0.111n   0.397/0.150n   0.418/94.970p
R_load = 50.000
[Rising Waveform]
R_fixture= 50.000
V_fixture= 0.0
V_fixture_min= 0.0
V_fixture_max= 0.0
|time   V(typ)   V(min)   V(max)
0s        1.134uV    6.183uV    517.4nV
400ps     -304.5uV   68.53uV    9.41mV
446ps     -1.581mV   23.81uV    87.12mV
518ps     9.619mV    -1.152mV   339.5mV
636ps     280mV      11.37mV    609mV
733ps     522.5mV    154.7mV    664.4mV
851ps     636.4mV    400.5mV    681.8mV
1.051ns   674.8mV    585.6mV    687.6mV
1.497ns   683.1mV    634.9mV    688.7mV
10ns      683.6mV    639.6mV    688.7mV
[Rising Waveform]
R_fixture= 50.000
V_fixture= 0.600
V_fixture_min= 0.583
V_fixture_max= 0.619
|time   V(typ)   V(min)   V(max)
0s        254.7mV    249.8mV    271mV
404ps     254.4mV    249.9mV    278.9mV
520ps     271mV      249.4mV    686.5mV
577ps     400.6mV    251.5mV    846.7mV
646ps     647.7mV    292mV      921.7mV
720ps     824.8mV    450.6mV    948.9mV
804ps     900.9mV    660.3mV    959.4mV
966ps     935.1mV    848mV      964.1mV
1.295ns   942.7mV    897.1mV    965.1mV
10ns      943.4mV    903.1mV    965.2mV
[Falling Waveform]
R_fixture= 50.000
V_fixture= 0.600
V_fixture_min= 0.583
V_fixture_max= 0.619
|time   V(typ)   V(min)   V(max)
0s        943.4mV    903.1mV    965.1mV
387ps     944.3mV    903.2mV    963.7mV
424ps     946.1mV    903.5mV    874.8mV
495ps     937.9mV    905.5mV    509.1mV
542ps     834.8mV    905.9mV    373.2mV
625ps     460.2mV    855.8mV    298.3mV
747ps     287.6mV    477.6mV    275.9mV
868ps     262.6mV    298.8mV    272mV
1.141ns   255.4mV    254.7mV    271mV
10ns      254.7mV    249.8mV    271mV
[Falling Waveform]
R_fixture= 50.000
V_fixture= 0.0
V_fixture_min= 0.0
V_fixture_max= 0.0
|time   V(typ)   V(min)   V(max)
0s        683.6mV    639.6mV    688.7mV
385ps     685.1mV    639.8mV    685.7mV
421ps     687.2mV    640.4mV    592.9mV
489ps     674.8mV    643.2mV    236.1mV
531ps     576.6mV    643.1mV    106.3mV
608ps     209.3mV    595.6mV    28.61mV
727ps     28.28mV    205.5mV    4.55mV
827ps     6.95mV     44.47mV    1.027mV
1.049ns   419.6uV    3.065mV    -27.1uV
10ns      1.135uV    6.173uV    523.7nV
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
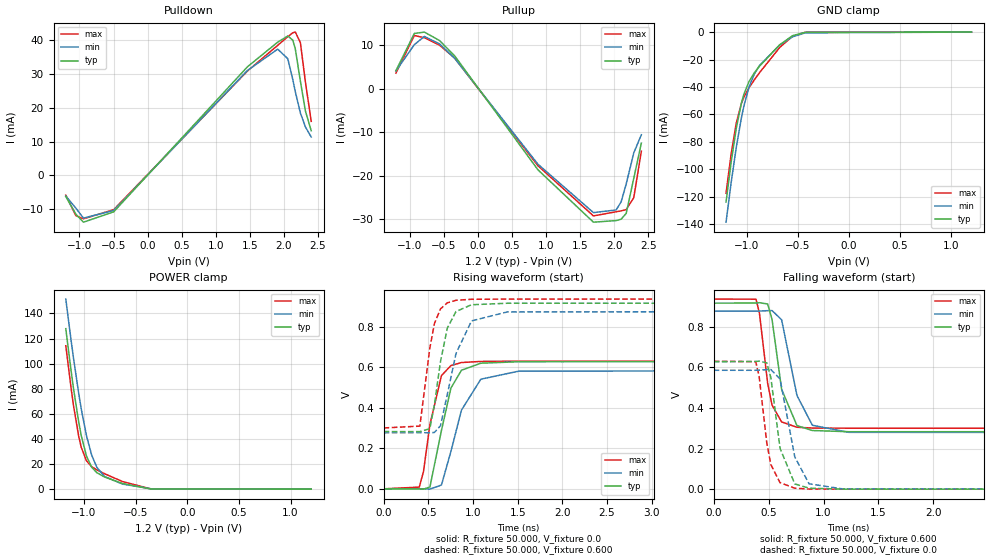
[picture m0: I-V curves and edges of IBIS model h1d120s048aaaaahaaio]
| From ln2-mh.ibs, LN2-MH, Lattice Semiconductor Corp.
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|   Model h1d120s048aaaaahaaio
[Model] h1d120s048aaaaahaaio
| Clamp models do not include dynamic input termination. Please refer to
| the h1d120axxxaaaaahaain model for input termination.
Model_type I/O
Polarity   Non-Inverting
Enable   Active-Low
Vinl =  0.500V
Vinh =  0.700V
Vmeas =  0.600V
Cref =  20.000pF
Rref =  50.000
Vref =  0.600V
C_comp   2.000pF   1.500pF   2.500pF
[Temperature Range]   25.000   0.125k   -40.000
[Voltage Range]   1.200V   1.160V   1.240V
[C Comp Corner]
C_comp   2.000pF   1.500pF   2.500pF
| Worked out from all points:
|   slope of the pulldown table from 0 to 0.18 V, typ, clamps not added: 44.5 ohm
|   slope of the pullup table from 0 to 0.18 V, typ, clamps not added: 44.9 ohm
|   GND clamp passes 1 mA (typ) near -0.49 V on its own axis
|   POWER clamp passes 1 mA (typ) near -0.45 V on its own axis
|   rising waveform, R_fixture 50.000, V_fixture 0.0: 20-80 % time 170ps typ, 228ps min, 139ps max; typ from 0 V to 0.627 V
|   rising waveform, R_fixture 50.000, V_fixture 0.600: 20-80 % time 144ps typ, 193ps min, 117ps max; typ from 0.282 V to 0.916 V
|   falling waveform, R_fixture 50.000, V_fixture 0.600: 20-80 % time 108ps typ, 141ps min, 94.9ps max; typ from 0.916 V to 0.282 V
|   falling waveform, R_fixture 50.000, V_fixture 0.0: 20-80 % time 101ps typ, 125ps min, 92.7ps max; typ from 0.627 V to 0 V
[Pulldown]
|Voltage   I(typ)   I(min)   I(max)
-1.2V     -6.256mA   -6.129mA   -5.843mA
-1.052V   -11.49mA   -9.695mA   -11.92mA
-941mV    -13.84mA   -12.63mA   -12.85mA
-497mV    -10.77mA   -10.38mA   -10.13mA
1.464V    32.07mA    30.98mA    30.83mA
1.908V    39.36mA    37.3mA     38.42mA
2.056V    41.19mA    34.47mA    40.98mA
2.13V     39.93mA    28.3mA     42.12mA
2.167V    37.33mA    24.67mA    42.34mA
2.241V    27.83mA    18.44mA    39.23mA
2.315V    18.99mA    14.3mA     27.54mA
2.4V      13.18mA    11.32mA    15.97mA
[Pullup]
|Voltage   I(typ)   I(min)   I(max)
-1.2V     4.095mA    4.031mA    3.539mA
-930mV    12.65mA    10.07mA    12.18mA
-782mV    12.96mA    11.96mA    11.66mA
-560mV    11.01mA    10.25mA    9.966mA
-338mV    7.489mA    6.936mA    6.974mA
883mV     -18.67mA   -17.38mA   -17.73mA
1.697V    -30.7mA    -28.5mA    -29.26mA
2.03V     -30.33mA   -27.89mA   -28.3mA
2.104V    -30.01mA   -26.01mA   -28.11mA
2.178V    -28.67mA   -21.9mA    -27.8mA
2.289V    -20.61mA   -14.78mA   -25.05mA
2.4V      -12.53mA   -10.62mA   -14.4mA
[GND_clamp]
|Voltage   I(typ)   I(min)   I(max)
-1.2V     -123.9mA   -138.6mA   -117.5mA
-1.15V    -94.78mA   -109.7mA   -88.79mA
-1.1V     -70.2mA    -84.05mA   -66.33mA
-1.05V    -51.82mA   -62.6mA    -51.98mA
-1.025V   -45.18mA   -53.76mA   -47.32mA
-975mV    -35.96mA   -40.02mA   -40.52mA
-925mV    -29.87mA   -30.81mA   -34.98mA
-875mV    -25.03mA   -24.57mA   -29.81mA
-675mV    -9.229mA   -9.412mA   -11.2mA
-550mV    -2.635mA   -3.442mA   -3.059mA
-425mV    -169.7uA   -547.4uA   -117uA
1.2V      0A         0A         0A
[POWER_clamp]
|Voltage   I(typ)   I(min)   I(max)
-1.175V   127.9mA    151.5mA    114.3mA
-1.125V   95.1mA     119.3mA    81.28mA
-1.1V     80mA       104.2mA    66.46mA
-1.05V    53.45mA    76.25mA    42.06mA
-1.025V   42.52mA    63.79mA    33.25mA
-975mV    26.42mA    42.64mA    22.65mA
-925mV    17.53mA    27.24mA    17.97mA
-875mV    13.15mA    17.46mA    15.37mA
-800mV    9.709mA    10.06mA    12.3mA
-625mV    4.479mA    4.015mA    6.021mA
-350mV    147.7uA    296.5uA    176.7uA
1.2V      0A         0A         0A
[Ramp]
| variable   typ   min   max
dV/dt_r   0.376/0.170n   0.351/0.228n   0.378/0.139n
dV/dt_f   0.380/0.122n   0.365/0.167n   0.383/99.061p
R_load = 50.000
[Rising Waveform]
R_fixture= 50.000
V_fixture= 0.0
V_fixture_min= 0.0
V_fixture_max= 0.0
|time   V(typ)   V(min)   V(max)
0s        1.282uV    6.961uV    584.4nV
399ps     -274.2uV   72.63uV    8.504mV
446ps     -1.668mV   30.58uV    85.15mV
518ps     9.27mV     -1.178mV   317.4mV
647ps     287.8mV    18.69mV    558.6mV
753ps     497.1mV    184.6mV    608mV
871ps     584.9mV    388.2mV    622.9mV
1.088ns   619.7mV    540.8mV    628.4mV
1.511ns   626.8mV    580.3mV    629.4mV
10ns      627.3mV    585.3mV    629.4mV
[Rising Waveform]
R_fixture= 50.000
V_fixture= 0.600
V_fixture_min= 0.583
V_fixture_max= 0.619
|time   V(typ)   V(min)   V(max)
0s        282.5mV    276.8mV    300.3mV
405ps     282.1mV    276.9mV    309.3mV
517ps     296.6mV    276.4mV    693.9mV
568ps     414mV      277.9mV    815mV
636ps     627.4mV    311.4mV    887.4mV
713ps     792.9mV    466.1mV    917.5mV
810ps     874.7mV    668.1mV    930mV
984ps     908mV      828.3mV    935mV
1.384ns   915.4mV    872.5mV    935.9mV
10ns      915.9mV    876.6mV    936mV
[Falling Waveform]
R_fixture= 50.000
V_fixture= 0.600
V_fixture_min= 0.583
V_fixture_max= 0.619
|time   V(typ)   V(min)   V(max)
0s        915.9mV    876.6mV    936mV
385ps     916.6mV    876.6mV    935.4mV
416ps     918.1mV    876.9mV    867.1mV
491ps     911.7mV    878.8mV    520.7mV
531ps     835.4mV    879.4mV    413.9mV
618ps     491.8mV    834.1mV    331.1mV
758ps     312.9mV    461.5mV    304.8mV
898ps     288.8mV    314.7mV    300.9mV
1.23ns    282.8mV    279.8mV    300.2mV
10ns      282.5mV    276.8mV    300.3mV
[Falling Waveform]
R_fixture= 50.000
V_fixture= 0.0
V_fixture_min= 0.0
V_fixture_max= 0.0
|time   V(typ)   V(min)   V(max)
0s        627.3mV    585.3mV    629.4mV
382ps     628.7mV    585.4mV    628mV
413ps     630.5mV    585.9mV    557.1mV
483ps     621.8mV    588.6mV    227.6mV
520ps     549.6mV    589.1mV    120.8mV
604ps     200.7mV    542.3mV    31.99mV
738ps     25.89mV    159.1mV    4.663mV
868ps     4.834mV    26.49mV    730.4uV
1.176ns   62.93uV    1.073mV    -68.27uV
10ns      1.284uV    6.953uV    592.4nV
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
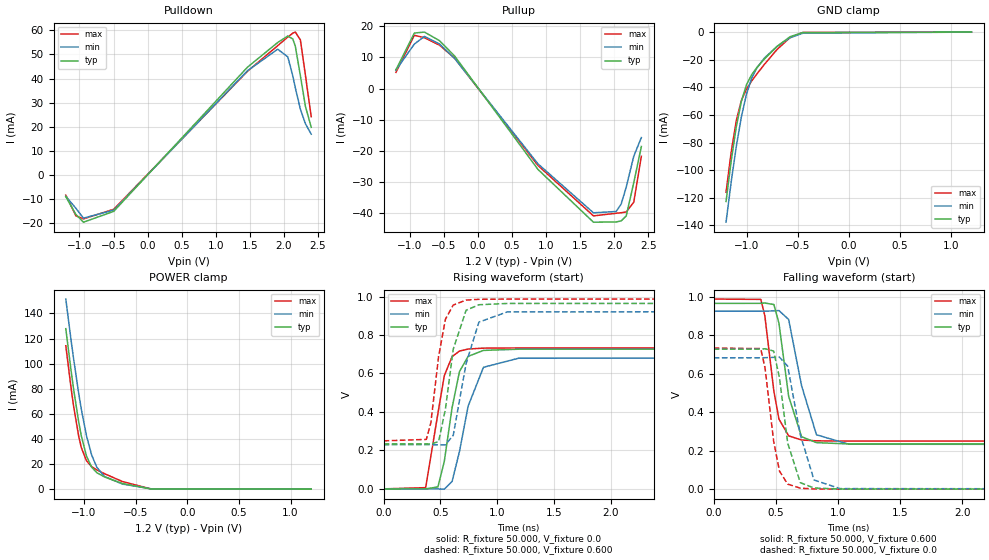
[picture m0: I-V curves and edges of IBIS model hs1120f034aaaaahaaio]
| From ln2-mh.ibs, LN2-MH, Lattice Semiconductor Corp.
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|   Model hs1120f034aaaaahaaio
[Model] hs1120f034aaaaahaaio
| Clamp models do not include dynamic input termination. Please refer to
| the hs1120axxxaaaaahaain model for input termination.
Model_type I/O
Polarity   Non-Inverting
Enable   Active-Low
Vinl =  0.500V
Vinh =  0.700V
Vmeas =  0.600V
Cref =  20.000pF
Rref =  50.000
Vref =  0.600V
C_comp   2.000pF   1.500pF   2.500pF
[Temperature Range]   25.000   0.125k   -40.000
[Voltage Range]   1.200V   1.160V   1.240V
[C Comp Corner]
C_comp   2.000pF   1.500pF   2.500pF
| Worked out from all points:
|   slope of the pulldown table from 0 to 0.18 V, typ, clamps not added: 31.9 ohm
|   slope of the pullup table from 0 to 0.18 V, typ, clamps not added: 32.3 ohm
|   GND clamp passes 1 mA (typ) near -0.50 V on its own axis
|   POWER clamp passes 1 mA (typ) near -0.45 V on its own axis
|   rising waveform, R_fixture 50.000, V_fixture 0.0: 20-80 % time 120ps typ, 147ps min, 108ps max; typ from 0 V to 0.727 V
|   rising waveform, R_fixture 50.000, V_fixture 0.600: 20-80 % time 106ps typ, 128ps min, 98.4ps max; typ from 0.234 V to 0.965 V
|   falling waveform, R_fixture 50.000, V_fixture 0.600: 20-80 % time 96.9ps typ, 124ps min, 88.7ps max; typ from 0.965 V to 0.234 V
|   falling waveform, R_fixture 50.000, V_fixture 0.0: 20-80 % time 93.4ps typ, 117ps min, 86.6ps max; typ from 0.727 V to 0 V
[Pulldown]
|Voltage   I(typ)   I(min)   I(max)
-1.2V     -8.96mA    -8.81mA    -8.326mA
-1.052V   -16.31mA   -13.79mA   -16.88mA
-941mV    -19.54mA   -17.86mA   -18.18mA
-497mV    -15.05mA   -14.52mA   -14.18mA
1.464V    44.67mA    43.19mA    42.97mA
1.908V    54.92mA    52.15mA    53.6mA
2.056V    57.61mA    48.99mA    57.18mA
2.13V     56.38mA    41.05mA    58.81mA
2.167V    53.35mA    36.11mA    59.24mA
2.241V    41.15mA    27.29mA    55.97mA
2.315V    28.48mA    21.26mA    41.29mA
2.4V      19.77mA    16.93mA    24.21mA
[Pullup]
|Voltage   I(typ)   I(min)   I(max)
-1.2V     6.003mA    5.923mA    5.177mA
-930mV    17.83mA    14.28mA    17.11mA
-782mV    18.14mA    16.75mA    16.33mA
-560mV    15.37mA    14.31mA    13.94mA
-338mV    10.42mA    9.655mA    9.718mA
883mV     -26mA      -24.21mA   -24.72mA
1.697V    -42.98mA   -39.96mA   -40.95mA
2.03V     -42.91mA   -39.54mA   -40.11mA
2.104V    -42.57mA   -37.16mA   -39.94mA
2.178V    -40.96mA   -31.7mA    -39.69mA
2.289V    -30.27mA   -21.74mA   -36.52mA
2.4V      -18.65mA   -15.77mA   -21.8mA
[GND_clamp]
|Voltage   I(typ)   I(min)   I(max)
-1.2V     -122.7mA   -137.7mA   -116mA
-1.15V    -93.48mA   -108.7mA   -87.06mA
-1.1V     -68.68mA   -82.93mA   -64.19mA
-1.05V    -50.06mA   -61.34mA   -49.53mA
-1V       -38.15mA   -44.88mA   -41.24mA
-950mV    -30.91mA   -33.54mA   -35.51mA
-900mV    -25.81mA   -26.1mA    -30.49mA
-825mV    -19.48mA   -18.8mA    -23.39mA
-700mV    -10.29mA   -10.29mA   -12.48mA
-575mV    -3.418mA   -4.142mA   -4.045mA
-450mV    -323.4uA   -814.3uA   -268.3uA
1.2V      0A         0A         0A
[POWER_clamp]
|Voltage   I(typ)   I(min)   I(max)
-1.175V   127.9mA    151.5mA    114.3mA
-1.125V   95.1mA     119.3mA    81.28mA
-1.1V     80mA       104.2mA    66.46mA
-1.05V    53.45mA    76.25mA    42.06mA
-1.025V   42.52mA    63.79mA    33.25mA
-975mV    26.42mA    42.64mA    22.65mA
-925mV    17.53mA    27.24mA    17.97mA
-875mV    13.15mA    17.46mA    15.37mA
-800mV    9.709mA    10.06mA    12.3mA
-625mV    4.479mA    4.015mA    6.021mA
-350mV    147.7uA    296.5uA    176.7uA
1.2V      0A         0A         0A
[Ramp]
| variable   typ   min   max
dV/dt_r   0.436/0.120n   0.409/0.147n   0.440/0.108n
dV/dt_f   0.439/0.104n   0.421/0.137n   0.444/92.214p
R_load = 50.000
[Rising Waveform]
R_fixture= 50.000
V_fixture= 0.0
V_fixture_min= 0.0
V_fixture_max= 0.0
|time   V(typ)   V(min)   V(max)
0s        1.021uV    5.586uV    466.9nV
370ps     58.06uV    43.37uV    6.262mV
478ps     10.12mV    -402.6uV   392.1mV
534ps     142.3mV    -1.574mV   588.3mV
603ps     423.1mV    38.93mV    687.8mV
668ps     609.8mV    194.6mV    716.4mV
744ps     689.1mV    430mV      727.1mV
879ps     719.9mV    632.1mV    731.7mV
1.189ns   726.2mV    679.3mV    732.6mV
10ns      726.5mV    682.1mV    732.6mV
[Rising Waveform]
R_fixture= 50.000
V_fixture= 0.600
V_fixture_min= 0.583
V_fixture_max= 0.619
|time   V(typ)   V(min)   V(max)
0s        233.9mV    229.5mV    249.7mV
376ps     233.9mV    229.6mV    257.2mV
416ps     233.5mV    229.6mV    344.2mV
484ps     245.5mV    229.1mV    688mV
544ps     414.4mV    228.9mV    882.1mV
613ps     726.1mV    278.6mV    956mV
726ps     928.5mV    651.1mV    981.6mV
839ps     957.3mV    867.2mV    985.7mV
1.09ns    964.1mV    920.2mV    986.8mV
10ns      964.5mV    923.8mV    986.9mV
[Falling Waveform]
R_fixture= 50.000
V_fixture= 0.600
V_fixture_min= 0.583
V_fixture_max= 0.619
|time   V(typ)   V(min)   V(max)
0s        964.5mV    923.8mV    986.9mV
379ps     964.8mV    923.9mV    985.2mV
411ps     966.3mV    924mV      900.8mV
484ps     958.5mV    925.6mV    508.2mV
525ps     861mV      927.3mV    363.6mV
603ps     481.8mV    880.8mV    276.7mV
707ps     272.5mV    537.2mV    255.3mV
827ps     241.5mV    282.3mV    251mV
1.087ns   234.7mV    233.3mV    249.8mV
10ns      233.9mV    229.5mV    249.7mV
[Falling Waveform]
R_fixture= 50.000
V_fixture= 0.0
V_fixture_min= 0.0
V_fixture_max= 0.0
|time   V(typ)   V(min)   V(max)
0s        726.5mV    682.1mV    732.6mV
378ps     727.1mV    682.1mV    729.8mV
413ps     729mV      682.4mV    628.7mV
482ps     716.9mV    684.4mV    249.2mV
529ps     578.4mV    685.1mV    93.95mV
595ps     240.1mV    638.8mV    26.37mV
697ps     33.69mV    282.4mV    5.018mV
807ps     6.128mV    47.85mV    1.145mV
1.018ns   610.4uV    2.767mV    156.9uV
10ns      1.005uV    5.563uV    453.7nV
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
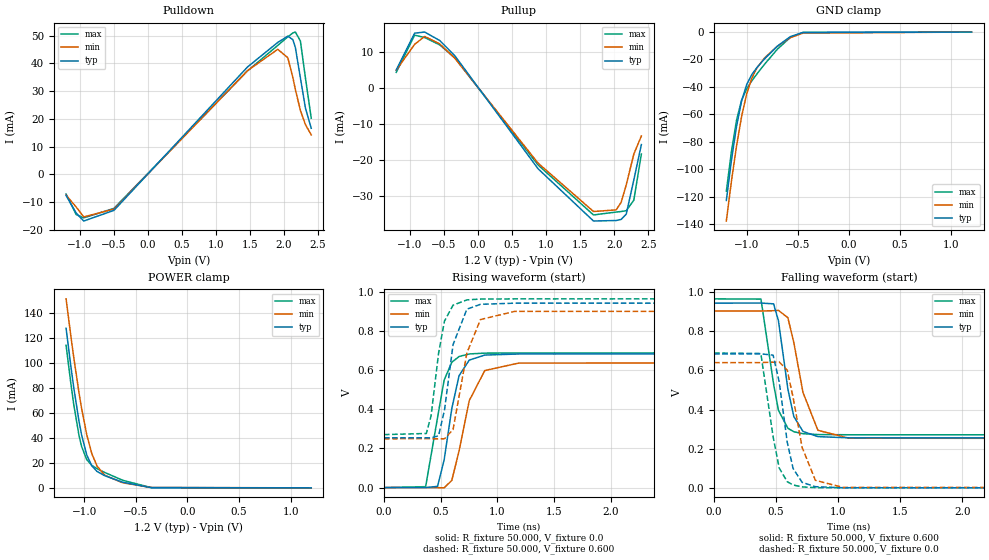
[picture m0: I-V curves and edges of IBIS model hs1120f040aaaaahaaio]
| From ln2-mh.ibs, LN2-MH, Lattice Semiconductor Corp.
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|   Model hs1120f040aaaaahaaio
[Model] hs1120f040aaaaahaaio
| Clamp models do not include dynamic input termination. Please refer to
| the hs1120axxxaaaaahaain model for input termination.
Model_type I/O
Polarity   Non-Inverting
Enable   Active-Low
Vinl =  0.500V
Vinh =  0.700V
Vmeas =  0.600V
Cref =  20.000pF
Rref =  50.000
Vref =  0.600V
C_comp   2.000pF   1.500pF   2.500pF
[Temperature Range]   25.000   0.125k   -40.000
[Voltage Range]   1.200V   1.160V   1.240V
[C Comp Corner]
C_comp   2.000pF   1.500pF   2.500pF
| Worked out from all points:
|   slope of the pulldown table from 0 to 0.18 V, typ, clamps not added: 36.9 ohm
|   slope of the pullup table from 0 to 0.18 V, typ, clamps not added: 37.3 ohm
|   GND clamp passes 1 mA (typ) near -0.50 V on its own axis
|   POWER clamp passes 1 mA (typ) near -0.45 V on its own axis
|   rising waveform, R_fixture 50.000, V_fixture 0.0: 20-80 % time 119ps typ, 147ps min, 109ps max; typ from 0 V to 0.684 V
|   rising waveform, R_fixture 50.000, V_fixture 0.600: 20-80 % time 103ps typ, 125ps min, 97.4ps max; typ from 0.255 V to 0.943 V
|   falling waveform, R_fixture 50.000, V_fixture 0.600: 20-80 % time 99.5ps typ, 127ps min, 91.7ps max; typ from 0.943 V to 0.255 V
|   falling waveform, R_fixture 50.000, V_fixture 0.0: 20-80 % time 96ps typ, 119ps min, 90ps max; typ from 0.684 V to 0 V
[Pulldown]
|Voltage   I(typ)   I(min)   I(max)
-1.2V     -7.641mA   -7.513mA   -7.121mA
-1.052V   -13.98mA   -11.81mA   -14.54mA
-941mV    -16.86mA   -15.38mA   -15.73mA
-497mV    -13.02mA   -12.56mA   -12.3mA
1.464V    38.7mA     37.38mA    37.29mA
1.908V    47.55mA    45.07mA    46.48mA
2.056V    49.83mA    42.04mA    49.58mA
2.13V     48.57mA    34.91mA    50.98mA
2.167V    45.71mA    30.58mA    51.31mA
2.241V    34.72mA    23.01mA    48.07mA
2.315V    23.86mA    17.9mA     34.67mA
2.4V      16.59mA    14.23mA    20.22mA
[Pullup]
|Voltage   I(typ)   I(min)   I(max)
-1.2V     5.078mA    5mA        4.395mA
-930mV    15.33mA    12.22mA    14.77mA
-782mV    15.65mA    14.42mA    14.12mA
-560mV    13.27mA    12.33mA    12.06mA
-338mV    9.009mA    8.335mA    8.419mA
883mV     -22.47mA   -20.9mA    -21.41mA
1.697V    -37.04mA   -34.39mA   -35.35mA
2.03V     -36.9mA    -33.94mA   -34.54mA
2.104V    -36.58mA   -31.79mA   -34.39mA
2.178V    -35.11mA   -26.95mA   -34.16mA
2.289V    -25.6mA    -18.39mA   -31.24mA
2.4V      -15.74mA   -13.34mA   -18.37mA
[GND_clamp]
|Voltage   I(typ)   I(min)   I(max)
-1.2V     -122.7mA   -137.7mA   -116mA
-1.15V    -93.48mA   -108.7mA   -87.06mA
-1.1V     -68.68mA   -82.93mA   -64.19mA
-1.05V    -50.06mA   -61.34mA   -49.53mA
-1V       -38.15mA   -44.88mA   -41.24mA
-950mV    -30.92mA   -33.54mA   -35.51mA
-900mV    -25.81mA   -26.1mA    -30.49mA
-825mV    -19.48mA   -18.8mA    -23.39mA
-700mV    -10.29mA   -10.29mA   -12.48mA
-575mV    -3.418mA   -4.142mA   -4.045mA
-450mV    -323.4uA   -814.3uA   -268.3uA
1.2V      0A         0A         0A
[POWER_clamp]
|Voltage   I(typ)   I(min)   I(max)
-1.175V   127.9mA    151.5mA    114.3mA
-1.125V   95.1mA     119.3mA    81.28mA
-1.1V     80mA       104.2mA    66.46mA
-1.05V    53.45mA    76.25mA    42.06mA
-1.025V   42.52mA    63.79mA    33.25mA
-975mV    26.42mA    42.64mA    22.65mA
-925mV    17.53mA    27.24mA    17.97mA
-875mV    13.15mA    17.46mA    15.37mA
-800mV    9.709mA    10.06mA    12.3mA
-625mV    4.479mA    4.015mA    6.021mA
-350mV    147.7uA    296.5uA    176.7uA
1.2V      0A         0A         0A
[Ramp]
| variable   typ   min   max
dV/dt_r   0.410/0.119n   0.384/0.147n   0.413/0.109n
dV/dt_f   0.414/0.107n   0.397/0.141n   0.418/94.572p
R_load = 50.000
[Rising Waveform]
R_fixture= 50.000
V_fixture= 0.0
V_fixture_min= 0.0
V_fixture_max= 0.0
|time   V(typ)   V(min)   V(max)
0s        1.134uV    6.183uV    517.4nV
368ps     64.36uV    47.7uV     4.774mV
473ps     6.327mV    -304uV     357.7mV
531ps     140.9mV    -1.275mV   549.5mV
599ps     404.8mV    37.11mV    641.2mV
663ps     572.3mV    187.7mV    670.4mV
753ps     652.2mV    445mV      683.5mV
890ps     677.8mV    598.7mV    687.7mV
1.19ns    683.3mV    636.9mV    688.6mV
10ns      683.6mV    639.6mV    688.7mV
[Rising Waveform]
R_fixture= 50.000
V_fixture= 0.600
V_fixture_min= 0.583
V_fixture_max= 0.619
|time   V(typ)   V(min)   V(max)
0s        254.7mV    249.8mV    271mV
374ps     254.8mV    249.9mV    276.7mV
416ps     254.3mV    249.9mV    367.1mV
482ps     265.1mV    249.5mV    686.6mV
534ps     395.3mV    249.6mV    851.2mV
610ps     731.4mV    296.9mV    933.1mV
732ps     912.5mV    688.7mV    960mV
852ps     937.3mV    859.5mV    964.1mV
1.152ns   943.2mV    901mV      965.1mV
10ns      943.4mV    903.1mV    965.2mV
[Falling Waveform]
R_fixture= 50.000
V_fixture= 0.600
V_fixture_min= 0.583
V_fixture_max= 0.619
|time   V(typ)   V(min)   V(max)
0s        943.4mV    903.1mV    965.1mV
378ps     943.7mV    903.1mV    963.9mV
480ps     939.6mV    904.6mV    529.4mV
519ps     852.9mV    906.3mV    395.9mV
595ps     504.4mV    868.8mV    304.1mV
643ps     364mV      741.6mV    286.6mV
717ps     288mV      486.5mV    276.4mV
837ps     261.6mV    293.9mV    272.2mV
1.087ns   255.4mV    253.5mV    271.1mV
10ns      254.7mV    249.8mV    271mV
[Falling Waveform]
R_fixture= 50.000
V_fixture= 0.0
V_fixture_min= 0.0
V_fixture_max= 0.0
|time   V(typ)   V(min)   V(max)
0s        683.6mV    639.6mV    688.7mV
377ps     684.3mV    639.7mV    686mV
476ps     678mV      641.7mV    261mV
525ps     541.6mV    642.6mV    101.3mV
590ps     232.6mV    600.2mV    31.42mV
637ps     99.01mV    461.8mV    14.62mV
710ps     27.92mV    206mV      4.859mV
817ps     5.931mV    38.31mV    1.177mV
1.037ns   535.1uV    2.439mV    139.1uV
10ns      1.118uV    6.161uV    504.3nV
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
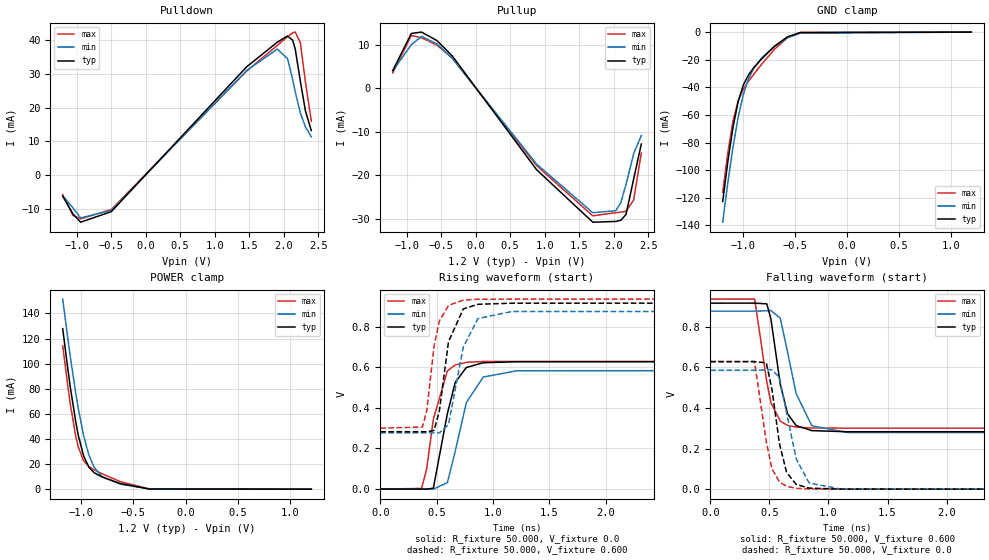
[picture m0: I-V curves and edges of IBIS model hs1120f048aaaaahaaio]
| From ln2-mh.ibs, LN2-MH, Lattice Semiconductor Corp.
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|   Model hs1120f048aaaaahaaio
[Model] hs1120f048aaaaahaaio
| Clamp models do not include dynamic input termination. Please refer to
| the hs1120axxxaaaaahaain model for input termination.
Model_type I/O
Polarity   Non-Inverting
Enable   Active-Low
Vinl =  0.500V
Vinh =  0.700V
Vmeas =  0.600V
Cref =  20.000pF
Rref =  50.000
Vref =  0.600V
C_comp   2.000pF   1.500pF   2.500pF
[Temperature Range]   25.000   0.125k   -40.000
[Voltage Range]   1.200V   1.160V   1.240V
[C Comp Corner]
C_comp   2.000pF   1.500pF   2.500pF
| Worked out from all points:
|   slope of the pulldown table from 0 to 0.18 V, typ, clamps not added: 44.5 ohm
|   slope of the pullup table from 0 to 0.18 V, typ, clamps not added: 44.9 ohm
|   GND clamp passes 1 mA (typ) near -0.50 V on its own axis
|   POWER clamp passes 1 mA (typ) near -0.45 V on its own axis
|   rising waveform, R_fixture 50.000, V_fixture 0.0: 20-80 % time 122ps typ, 154ps min, 109ps max; typ from 0 V to 0.627 V
|   rising waveform, R_fixture 50.000, V_fixture 0.600: 20-80 % time 102ps typ, 128ps min, 91.7ps max; typ from 0.282 V to 0.916 V
|   falling waveform, R_fixture 50.000, V_fixture 0.600: 20-80 % time 106ps typ, 137ps min, 95.6ps max; typ from 0.916 V to 0.282 V
|   falling waveform, R_fixture 50.000, V_fixture 0.0: 20-80 % time 102ps typ, 127ps min, 94.5ps max; typ from 0.627 V to 0 V
[Pulldown]
|Voltage   I(typ)   I(min)   I(max)
-1.2V     -6.208mA   -6.101mA   -5.769mA
-1.052V   -11.44mA   -9.656mA   -11.9mA
-941mV    -13.91mA   -12.66mA   -12.94mA
-497mV    -10.79mA   -10.4mA    -10.15mA
1.464V    32.07mA    30.98mA    30.83mA
1.908V    39.36mA    37.3mA     38.42mA
2.056V    41.19mA    34.47mA    40.98mA
2.13V     39.93mA    28.3mA     42.12mA
2.167V    37.33mA    24.67mA    42.34mA
2.241V    27.83mA    18.44mA    39.23mA
2.315V    18.99mA    14.3mA     27.54mA
2.4V      13.18mA    11.32mA    15.97mA
[Pullup]
|Voltage   I(typ)   I(min)   I(max)
-1.2V     4.095mA    4.031mA    3.539mA
-930mV    12.65mA    10.07mA    12.18mA
-782mV    12.96mA    11.96mA    11.66mA
-560mV    11.01mA    10.25mA    9.966mA
-338mV    7.489mA    6.936mA    6.974mA
883mV     -18.67mA   -17.38mA   -17.73mA
1.697V    -30.75mA   -28.57mA   -29.29mA
2.03V     -30.58mA   -28.11mA   -28.56mA
2.104V    -30.3mA    -26.24mA   -28.44mA
2.178V    -28.99mA   -22.09mA   -28.24mA
2.289V    -20.83mA   -14.98mA   -25.65mA
2.4V      -12.77mA   -10.84mA   -14.84mA
[GND_clamp]
|Voltage   I(typ)   I(min)   I(max)
-1.2V     -122.7mA   -137.7mA   -116mA
-1.15V    -93.48mA   -108.7mA   -87.06mA
-1.1V     -68.68mA   -82.93mA   -64.19mA
-1.05V    -50.06mA   -61.34mA   -49.53mA
-1V       -38.15mA   -44.88mA   -41.24mA
-950mV    -30.91mA   -33.54mA   -35.51mA
-900mV    -25.81mA   -26.1mA    -30.49mA
-825mV    -19.48mA   -18.8mA    -23.39mA
-700mV    -10.29mA   -10.29mA   -12.48mA
-575mV    -3.418mA   -4.142mA   -4.045mA
-450mV    -323.4uA   -814.3uA   -268.3uA
1.2V      0A         0A         0A
[POWER_clamp]
|Voltage   I(typ)   I(min)   I(max)
-1.175V   127.9mA    151.5mA    114.3mA
-1.125V   95.1mA     119.3mA    81.28mA
-1.1V     80mA       104.2mA    66.46mA
-1.05V    53.45mA    76.25mA    42.06mA
-1.025V   42.52mA    63.79mA    33.25mA
-975mV    26.42mA    42.64mA    22.65mA
-925mV    17.53mA    27.24mA    17.97mA
-875mV    13.15mA    17.46mA    15.37mA
-800mV    9.709mA    10.06mA    12.3mA
-625mV    4.479mA    4.015mA    6.021mA
-350mV    147.7uA    296.5uA    176.7uA
1.2V      0A         0A         0A
[Ramp]
| variable   typ   min   max
dV/dt_r   0.376/0.122n   0.351/0.154n   0.378/0.109n
dV/dt_f   0.380/0.114n   0.365/0.153n   0.383/96.909p
R_load = 50.000
[Rising Waveform]
R_fixture= 50.000
V_fixture= 0.0
V_fixture_min= 0.0
V_fixture_max= 0.0
|time   V(typ)   V(min)   V(max)
0s        1.282uV    6.961uV    584.4nV
366ps     75.36uV    54.82uV    3.061mV
411ps     -457uV     75.71uV    97.35mV
471ps     4.766mV    -265.9uV   344.2mV
595ps     371.4mV    31.6mV     581.7mV
665ps     525.6mV    187.1mV    611.3mV
763ps     598.8mV    425.1mV    624.4mV
913ps     622.4mV    552mV      628.5mV
1.213ns   627.1mV    582.8mV    629.3mV
10ns      627.3mV    585.3mV    629.4mV
[Rising Waveform]
R_fixture= 50.000
V_fixture= 0.600
V_fixture_min= 0.583
V_fixture_max= 0.619
|time   V(typ)   V(min)   V(max)
0s        282.5mV    276.8mV    300.3mV
374ps     282.5mV    276.9mV    305.5mV
413ps     282.1mV    276.9mV    387.3mV
477ps     288.6mV    276.5mV    705mV
524ps     383.9mV    276.7mV    827.7mV
605ps     725.1mV    317.2mV    904.6mV
736ps     887.2mV    699.1mV    930.9mV
866ps     910.3mV    839.9mV    935mV
1.165ns   915.6mV    874.5mV    935.9mV
10ns      915.9mV    876.6mV    936mV
[Falling Waveform]
R_fixture= 50.000
V_fixture= 0.600
V_fixture_min= 0.583
V_fixture_max= 0.619
|time   V(typ)   V(min)   V(max)
0s        915.9mV    876.6mV    936mV
376ps     916.1mV    876.6mV    936mV
478ps     912.4mV    878mV      529mV
513ps     838.7mV    879.5mV    426.3mV
592ps     516.8mV    842.2mV    335mV
654ps     371.2mV    675mV      314.1mV
727ps     312.9mV    469.2mV    305.3mV
860ps     288.2mV    311.8mV    301.2mV
1.157ns   282.8mV    279.1mV    300.3mV
10ns      282.5mV    276.8mV    300.3mV
[Falling Waveform]
R_fixture= 50.000
V_fixture= 0.0
V_fixture_min= 0.0
V_fixture_max= 0.0
|time   V(typ)   V(min)   V(max)
0s        627.3mV    585.3mV    629.4mV
374ps     627.9mV    585.3mV    628.8mV
474ps     622.2mV    587.3mV    234.2mV
522ps     491.1mV    588.3mV    100.9mV
586ps     221.7mV    548.4mV    35.06mV
646ps     82.44mV    375.5mV    14.07mV
727ps     23.31mV    149mV      4.466mV
837ps     5.3mV      29.94mV    1.096mV
1.097ns   356.5uV    1.565mV    94.36uV
10ns      1.266uV    6.939uV    570.4nV
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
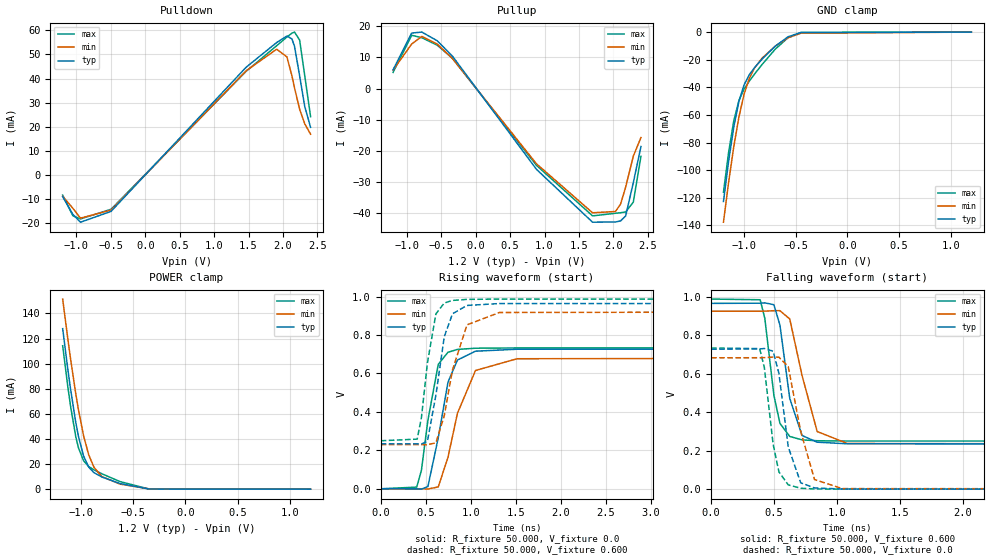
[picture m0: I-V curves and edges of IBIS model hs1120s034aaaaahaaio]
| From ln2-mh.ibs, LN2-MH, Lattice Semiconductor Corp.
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|   Model hs1120s034aaaaahaaio
[Model] hs1120s034aaaaahaaio
| Clamp models do not include dynamic input termination. Please refer to
| the hs1120axxxaaaaahaain model for input termination.
Model_type I/O
Polarity   Non-Inverting
Enable   Active-Low
Vinl =  0.500V
Vinh =  0.700V
Vmeas =  0.600V
Cref =  20.000pF
Rref =  50.000
Vref =  0.600V
C_comp   2.000pF   1.500pF   2.500pF
[Temperature Range]   25.000   0.125k   -40.000
[Voltage Range]   1.200V   1.160V   1.240V
[C Comp Corner]
C_comp   2.000pF   1.500pF   2.500pF
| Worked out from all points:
|   slope of the pulldown table from 0 to 0.18 V, typ, clamps not added: 31.9 ohm
|   slope of the pullup table from 0 to 0.18 V, typ, clamps not added: 32.3 ohm
|   GND clamp passes 1 mA (typ) near -0.50 V on its own axis
|   POWER clamp passes 1 mA (typ) near -0.45 V on its own axis
|   rising waveform, R_fixture 50.000, V_fixture 0.0: 20-80 % time 164ps typ, 221ps min, 131ps max; typ from 0 V to 0.727 V
|   rising waveform, R_fixture 50.000, V_fixture 0.600: 20-80 % time 139ps typ, 185ps min, 113ps max; typ from 0.234 V to 0.965 V
|   falling waveform, R_fixture 50.000, V_fixture 0.600: 20-80 % time 96.8ps typ, 125ps min, 86.1ps max; typ from 0.965 V to 0.234 V
|   falling waveform, R_fixture 50.000, V_fixture 0.0: 20-80 % time 90.8ps typ, 114ps min, 83.2ps max; typ from 0.726 V to 0 V
[Pulldown]
|Voltage   I(typ)   I(min)   I(max)
-1.2V     -8.96mA    -8.81mA    -8.326mA
-1.052V   -16.31mA   -13.79mA   -16.88mA
-941mV    -19.54mA   -17.86mA   -18.18mA
-497mV    -15.05mA   -14.52mA   -14.18mA
1.464V    44.67mA    43.19mA    42.97mA
1.908V    54.92mA    52.15mA    53.6mA
2.056V    57.61mA    48.99mA    57.18mA
2.13V     56.38mA    41.05mA    58.81mA
2.167V    53.35mA    36.11mA    59.24mA
2.241V    41.15mA    27.29mA    55.97mA
2.315V    28.48mA    21.26mA    41.29mA
2.4V      19.77mA    16.93mA    24.21mA
[Pullup]
|Voltage   I(typ)   I(min)   I(max)
-1.2V     6.003mA    5.923mA    5.177mA
-930mV    17.83mA    14.28mA    17.11mA
-782mV    18.14mA    16.75mA    16.33mA
-560mV    15.37mA    14.31mA    13.94mA
-338mV    10.42mA    9.655mA    9.718mA
883mV     -26mA      -24.21mA   -24.72mA
1.697V    -42.98mA   -39.96mA   -40.95mA
2.03V     -42.91mA   -39.54mA   -40.11mA
2.104V    -42.57mA   -37.16mA   -39.94mA
2.178V    -40.96mA   -31.7mA    -39.69mA
2.289V    -30.27mA   -21.74mA   -36.52mA
2.4V      -18.65mA   -15.77mA   -21.8mA
[GND_clamp]
|Voltage   I(typ)   I(min)   I(max)
-1.2V     -122.7mA   -137.7mA   -116mA
-1.15V    -93.48mA   -108.7mA   -87.06mA
-1.1V     -68.68mA   -82.93mA   -64.19mA
-1.05V    -50.06mA   -61.34mA   -49.53mA
-1V       -38.15mA   -44.88mA   -41.24mA
-950mV    -30.91mA   -33.54mA   -35.51mA
-900mV    -25.81mA   -26.1mA    -30.49mA
-825mV    -19.48mA   -18.8mA    -23.39mA
-700mV    -10.29mA   -10.29mA   -12.48mA
-575mV    -3.418mA   -4.142mA   -4.045mA
-450mV    -323.4uA   -814.3uA   -268.3uA
1.2V      0A         0A         0A
[POWER_clamp]
|Voltage   I(typ)   I(min)   I(max)
-1.175V   127.9mA    151.5mA    114.3mA
-1.125V   95.1mA     119.3mA    81.28mA
-1.1V     80mA       104.2mA    66.46mA
-1.05V    53.45mA    76.25mA    42.06mA
-1.025V   42.52mA    63.79mA    33.25mA
-975mV    26.42mA    42.64mA    22.65mA
-925mV    17.53mA    27.24mA    17.97mA
-875mV    13.15mA    17.46mA    15.37mA
-800mV    9.709mA    10.06mA    12.3mA
-625mV    4.479mA    4.015mA    6.021mA
-350mV    147.7uA    296.5uA    176.7uA
1.2V      0A         0A         0A
[Ramp]
| variable   typ   min   max
dV/dt_r   0.436/0.164n   0.409/0.221n   0.440/0.131n
dV/dt_f   0.439/0.108n   0.421/0.145n   0.444/91.674p
R_load = 50.000
[Rising Waveform]
R_fixture= 50.000
V_fixture= 0.0
V_fixture_min= 0.0
V_fixture_max= 0.0
|time   V(typ)   V(min)   V(max)
0s        1.021uV    5.586uV    466.9nV
400ps     -330.8uV   66.96uV    8.487mV
452ps     -2.15mV    -26.38uV   95.23mV
524ps     11.13mV    -1.499mV   355.7mV
639ps     265mV      9.512mV    647.1mV
747ps     554.6mV    163.7mV    710.1mV
852ps     669.6mV    392.6mV    724.9mV
1.052ns   715.7mV    615.2mV    731.2mV
1.513ns   725.9mV    676.4mV    732.6mV
10ns      726.5mV    682.1mV    732.6mV
[Rising Waveform]
R_fixture= 50.000
V_fixture= 0.600
V_fixture_min= 0.583
V_fixture_max= 0.619
|time   V(typ)   V(min)   V(max)
0s        233.9mV    229.5mV    249.7mV
405ps     233.5mV    229.6mV    258.2mV
452ps     232.9mV    229.4mV    369.8mV
519ps     247.3mV    228.9mV    655.5mV
613ps     487.8mV    239.2mV    909.8mV
706ps     791.3mV    381mV      966.3mV
797ps     910.1mV    618.3mV    979.9mV
958ps     953.7mV    852.8mV    985.3mV
1.317ns   963.6mV    917mV      986.8mV
10ns      964.5mV    923.8mV    986.9mV
[Falling Waveform]
R_fixture= 50.000
V_fixture= 0.600
V_fixture_min= 0.583
V_fixture_max= 0.619
|time   V(typ)   V(min)   V(max)
0s        964.5mV    923.8mV    986.9mV
390ps     965.4mV    924mV      983.3mV
427ps     967.4mV    924.2mV    886.7mV
499ps     957.4mV    926.4mV    487.6mV
547ps     851.6mV    926.7mV    341.8mV
625ps     471.3mV    883.5mV    273.7mV
723ps     278.6mV    589.5mV    255.8mV
843ps     243.9mV    299.1mV    251.4mV
1.083ns   235.5mV    237.1mV    249.9mV
10ns      233.9mV    229.5mV    249.7mV
[Falling Waveform]
R_fixture= 50.000
V_fixture= 0.0
V_fixture_min= 0.0
V_fixture_max= 0.0
|time   V(typ)   V(min)   V(max)
0s        726.5mV    682.1mV    732.6mV
386ps     728mV      682.3mV    729.7mV
423ps     730.1mV    682.8mV    632.2mV
493ps     716.2mV    685.7mV    233.4mV
539ps     601.2mV    685.1mV    89.41mV
613ps     219.4mV    635.9mV    22.35mV
712ps     33.07mV    299.8mV    4.741mV
822ps     6.347mV    49.89mV    1.179mV
1.043ns   719.1uV    2.893mV    177uV
10ns      1.006uV    5.563uV    454.4nV
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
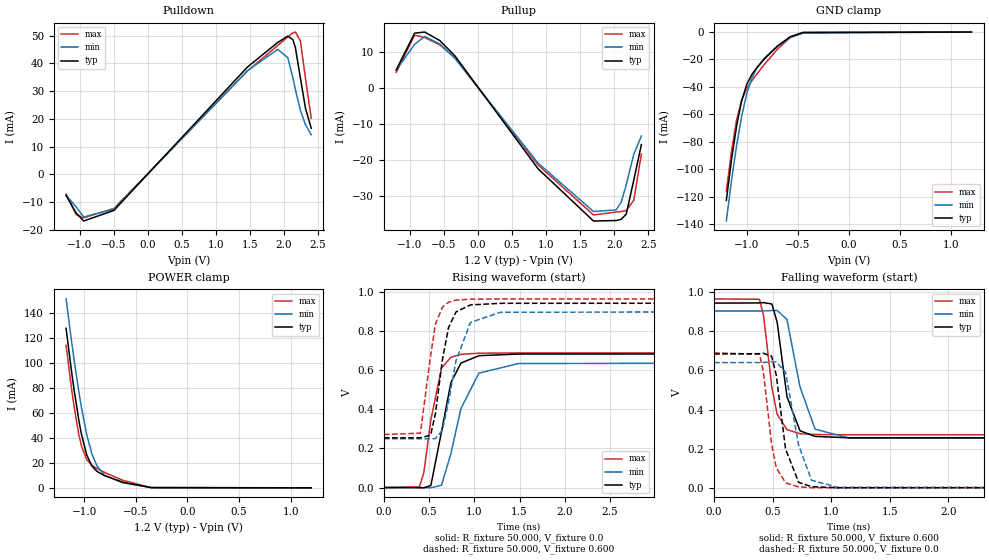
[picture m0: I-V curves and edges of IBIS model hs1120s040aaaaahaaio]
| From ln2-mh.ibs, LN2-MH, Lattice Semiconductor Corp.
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|   Model hs1120s040aaaaahaaio
[Model] hs1120s040aaaaahaaio
| Clamp models do not include dynamic input termination. Please refer to
| the hs1120axxxaaaaahaain model for input termination.
Model_type I/O
Polarity   Non-Inverting
Enable   Active-Low
Vinl =  0.500V
Vinh =  0.700V
Vmeas =  0.600V
Cref =  20.000pF
Rref =  50.000
Vref =  0.600V
C_comp   2.000pF   1.500pF   2.500pF
[Temperature Range]   25.000   0.125k   -40.000
[Voltage Range]   1.200V   1.160V   1.240V
[C Comp Corner]
C_comp   2.000pF   1.500pF   2.500pF
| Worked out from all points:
|   slope of the pulldown table from 0 to 0.18 V, typ, clamps not added: 36.9 ohm
|   slope of the pullup table from 0 to 0.18 V, typ, clamps not added: 37.3 ohm
|   GND clamp passes 1 mA (typ) near -0.50 V on its own axis
|   POWER clamp passes 1 mA (typ) near -0.45 V on its own axis
|   rising waveform, R_fixture 50.000, V_fixture 0.0: 20-80 % time 159ps typ, 214ps min, 131ps max; typ from 0 V to 0.684 V
|   rising waveform, R_fixture 50.000, V_fixture 0.600: 20-80 % time 133ps typ, 178ps min, 111ps max; typ from 0.255 V to 0.943 V
|   falling waveform, R_fixture 50.000, V_fixture 0.600: 20-80 % time 99ps typ, 128ps min, 89.1ps max; typ from 0.943 V to 0.255 V
|   falling waveform, R_fixture 50.000, V_fixture 0.0: 20-80 % time 93.3ps typ, 116ps min, 86.9ps max; typ from 0.684 V to 0 V
[Pulldown]
|Voltage   I(typ)   I(min)   I(max)
-1.2V     -7.641mA   -7.513mA   -7.121mA
-1.052V   -13.98mA   -11.81mA   -14.54mA
-941mV    -16.86mA   -15.38mA   -15.73mA
-497mV    -13.02mA   -12.56mA   -12.3mA
1.464V    38.7mA     37.38mA    37.29mA
1.908V    47.55mA    45.07mA    46.48mA
2.056V    49.83mA    42.04mA    49.58mA
2.13V     48.57mA    34.91mA    50.98mA
2.167V    45.71mA    30.58mA    51.31mA
2.241V    34.72mA    23.01mA    48.07mA
2.315V    23.86mA    17.9mA     34.67mA
2.4V      16.59mA    14.23mA    20.22mA
[Pullup]
|Voltage   I(typ)   I(min)   I(max)
-1.2V     5.078mA    5mA        4.395mA
-930mV    15.33mA    12.22mA    14.77mA
-782mV    15.65mA    14.42mA    14.12mA
-560mV    13.27mA    12.33mA    12.06mA
-338mV    9.009mA    8.335mA    8.419mA
883mV     -22.47mA   -20.9mA    -21.41mA
1.697V    -37.04mA   -34.39mA   -35.35mA
2.03V     -36.9mA    -33.94mA   -34.54mA
2.104V    -36.58mA   -31.79mA   -34.39mA
2.178V    -35.11mA   -26.95mA   -34.16mA
2.289V    -25.6mA    -18.39mA   -31.24mA
2.4V      -15.74mA   -13.34mA   -18.37mA
[GND_clamp]
|Voltage   I(typ)   I(min)   I(max)
-1.2V     -122.7mA   -137.7mA   -116mA
-1.15V    -93.48mA   -108.7mA   -87.06mA
-1.1V     -68.68mA   -82.93mA   -64.19mA
-1.05V    -50.06mA   -61.34mA   -49.53mA
-1V       -38.15mA   -44.88mA   -41.24mA
-950mV    -30.92mA   -33.54mA   -35.51mA
-900mV    -25.81mA   -26.1mA    -30.49mA
-825mV    -19.48mA   -18.8mA    -23.39mA
-700mV    -10.29mA   -10.29mA   -12.48mA
-575mV    -3.418mA   -4.142mA   -4.045mA
-450mV    -323.4uA   -814.3uA   -268.3uA
1.2V      0A         0A         0A
[POWER_clamp]
|Voltage   I(typ)   I(min)   I(max)
-1.175V   127.9mA    151.5mA    114.3mA
-1.125V   95.1mA     119.3mA    81.28mA
-1.1V     80mA       104.2mA    66.46mA
-1.05V    53.45mA    76.25mA    42.06mA
-1.025V   42.52mA    63.79mA    33.25mA
-975mV    26.42mA    42.64mA    22.65mA
-925mV    17.53mA    27.24mA    17.97mA
-875mV    13.15mA    17.46mA    15.37mA
-800mV    9.709mA    10.06mA    12.3mA
-625mV    4.479mA    4.015mA    6.021mA
-350mV    147.7uA    296.5uA    176.7uA
1.2V      0A         0A         0A
[Ramp]
| variable   typ   min   max
dV/dt_r   0.410/0.159n   0.384/0.214n   0.413/0.132n
dV/dt_f   0.414/0.110n   0.397/0.149n   0.418/93.905p
R_load = 50.000
[Rising Waveform]
R_fixture= 50.000
V_fixture= 0.0
V_fixture_min= 0.0
V_fixture_max= 0.0
|time   V(typ)   V(min)   V(max)
0s        1.134uV    6.183uV    517.4nV
392ps     -153.9uV   61.97uV    4.311mV
441ps     -1.332mV   51.19uV    75.27mV
519ps     10.52mV    -1.2mV     346.6mV
637ps     286.2mV    12.28mV    610.8mV
741ps     537mV      174.4mV    666.5mV
852ps     636.9mV    404.2mV    681.6mV
1.051ns   674.5mV    585.6mV    687.4mV
1.492ns   683mV      634.6mV    688.6mV
10ns      683.6mV    639.6mV    688.7mV
[Rising Waveform]
R_fixture= 50.000
V_fixture= 0.600
V_fixture_min= 0.583
V_fixture_max= 0.619
|time   V(typ)   V(min)   V(max)
0s        254.7mV    249.8mV    271mV
403ps     254.4mV    249.9mV    278.4mV
516ps     268.2mV    249.3mV    674mV
570ps     379.7mV    250.6mV    835.7mV
647ps     654.2mV    293.9mV    923.3mV
715ps     818.8mV    438.9mV    948.1mV
797ps     898.1mV    648.3mV    958.7mV
957ps     934.2mV    844.3mV    963.8mV
1.287ns   942.5mV    896.6mV    965mV
10ns      943.4mV    903.1mV    965.2mV
[Falling Waveform]
R_fixture= 50.000
V_fixture= 0.600
V_fixture_min= 0.583
V_fixture_max= 0.619
|time   V(typ)   V(min)   V(max)
0s        943.4mV    903.1mV    965.1mV
388ps     944.3mV    903.2mV    962.8mV
423ps     946mV      903.4mV    878.7mV
494ps     938.8mV    905.5mV    511.9mV
539ps     845.6mV    906mV      375.7mV
623ps     465.1mV    859.1mV    297.3mV
734ps     291.6mV    516.4mV    276.7mV
863ps     262.7mV    299.7mV    272.4mV
1.152ns   255.6mV    254.5mV    271.1mV
10ns      254.7mV    249.8mV    271mV
[Falling Waveform]
R_fixture= 50.000
V_fixture= 0.0
V_fixture_min= 0.0
V_fixture_max= 0.0
|time   V(typ)   V(min)   V(max)
0s        683.6mV    639.6mV    688.7mV
388ps     685.3mV    639.8mV    682.7mV
420ps     687.2mV    640.4mV    597.2mV
492ps     672mV      643.3mV    221.4mV
531ps     576.6mV    643.1mV    103.7mV
611ps     197.8mV    590.3mV    25.37mV
723ps     27.84mV    216.5mV    4.687mV
833ps     5.943mV    38.64mV    1.17mV
1.056ns   641.3uV    2.655mV    155.9uV
10ns      1.119uV    6.161uV    504.4nV
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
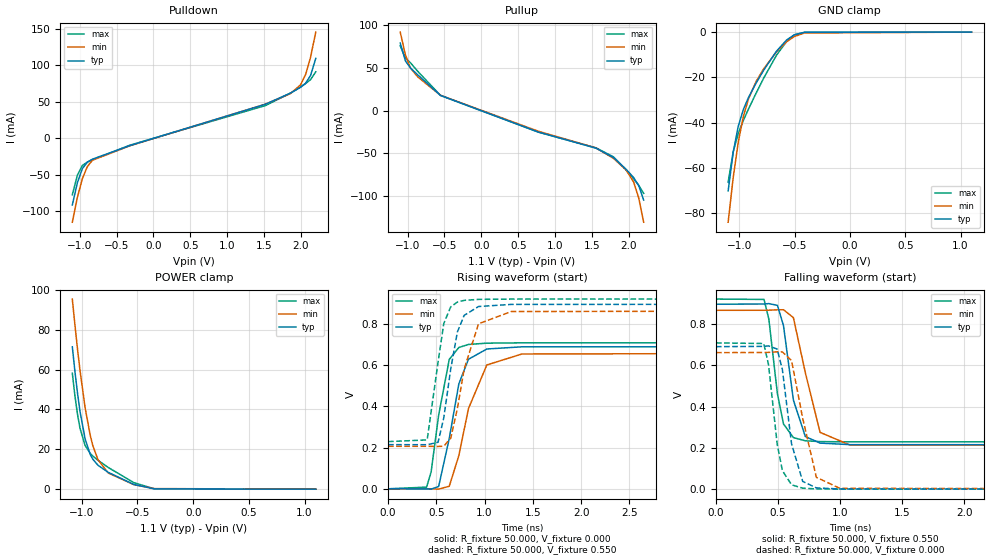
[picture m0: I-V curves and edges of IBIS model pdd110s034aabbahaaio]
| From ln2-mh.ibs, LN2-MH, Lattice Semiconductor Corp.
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|   Model pdd110s034aabbahaaio
[Model] pdd110s034aabbahaaio
| Clamp models do not include dynamic input termination. Please refer to
| the pdd110axxxaabbahaain model for input termination.
Model_type I/O
Polarity   Non-Inverting
Enable   Active-Low
Vinl =  0.700V
Vinh =  0.900V
Vmeas =  0.550V
Cref =  20.000pF
Rref =  50.000
Vref =  0.600V
C_comp   2.000pF   1.500pF   2.500pF
[Temperature Range]   25.000   0.125k   -40.000
[Voltage Range]   1.100V   1.070V   1.130V
[C Comp Corner]
C_comp   2.000pF   1.500pF   2.500pF
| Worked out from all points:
|   slope of the pulldown table from 0 to 0.165 V, typ, clamps not added: 31.9 ohm
|   slope of the pullup table from 0 to 0.165 V, typ, clamps not added: 29.4 ohm
|   GND clamp passes 1 mA (typ) near -0.49 V on its own axis
|   POWER clamp passes 1 mA (typ) near -0.45 V on its own axis
|   rising waveform, R_fixture 50.000, V_fixture 0.000: 20-80 % time 161ps typ, 204ps min, 128ps max; typ from 0 V to 0.691 V
|   rising waveform, R_fixture 50.000, V_fixture 0.550: 20-80 % time 138ps typ, 170ps min, 110ps max; typ from 0.214 V to 0.897 V
|   falling waveform, R_fixture 50.000, V_fixture 0.550: 20-80 % time 96.6ps typ, 123ps min, 85.8ps max; typ from 0.897 V to 0.214 V
|   falling waveform, R_fixture 50.000, V_fixture 0.000: 20-80 % time 91.6ps typ, 112ps min, 83.1ps max; typ from 0.691 V to 0 V
[Pulldown]
|Voltage   I(typ)   I(min)   I(max)
-1.1V     -91.24mA   -114.8mA   -77.34mA
-1.032V   -61.08mA   -81.09mA   -50.68mA
-964mV    -41.58mA   -55.26mA   -37.32mA
-896mV    -32.67mA   -38.76mA   -32.49mA
-828mV    -28.69mA   -30.15mA   -29.47mA
-318mV    -10.03mA   -10.28mA   -9.481mA
1.518V    46.44mA    46.55mA    44.66mA
1.858V    61.77mA    61.08mA    61.62mA
1.994V    69.6mA     72.99mA    70.2mA
2.062V    75.1mA     86.91mA    74.73mA
2.13V     85.87mA    110.7mA    80.09mA
2.2V      109.1mA    145.1mA    90.74mA
[Pullup]
|Voltage   I(typ)   I(min)   I(max)
-1.1V     79.31mA    92.23mA    76.01mA
-1.03V    58.44mA    65.43mA    61.84mA
-962mV    50.19mA    50.1mA     56.27mA
-860mV    41.79mA    39.4mA     45.92mA
-554mV    17.87mA    18.04mA    17.86mA
772mV     -25.08mA   -24.14mA   -25.2mA
1.554V    -44mA      -43.77mA   -43.68mA
1.792V    -55.1mA    -56.04mA   -54.26mA
1.962V    -68.78mA   -69.58mA   -69.63mA
2.064V    -78.52mA   -83.78mA   -80.12mA
2.132V    -87.69mA   -102.1mA   -87.58mA
2.2V      -104.9mA   -130.9mA   -97.03mA
[GND_clamp]
|Voltage   I(typ)   I(min)   I(max)
-1.1V     -70.18mA   -84.03mA   -66.3mA
-1.054V   -53.01mA   -64.11mA   -52.8mA
-1.008V   -41.49mA   -48.48mA   -44.7mA
-962mV    -34.14mA   -37.22mA   -38.97mA
-916mV    -28.9mA    -29.49mA   -33.98mA
-847mV    -22.51mA   -21.79mA   -26.95mA
-778mV    -16.79mA   -16.17mA   -20.26mA
-663mV    -8.43mA    -8.709mA   -10.22mA
-571mV    -3.466mA   -4.237mA   -4.094mA
-502mV    -1.18mA    -1.941mA   -1.256mA
-410mV    -105.5uA   -402.4uA   -63.37uA
1.1V      0A         0A         0A
[POWER_clamp]
|Voltage   I(typ)   I(min)   I(max)
-1.085V   71.41mA    95.35mA    58.18mA
-1.062V   59.23mA    82.55mA    46.99mA
-1.039V   48.36mA    70.56mA    37.71mA
-1.016V   38.97mA    59.53mA    30.53mA
-970mV    25.17mA    40.76mA    21.88mA
-924mV    17.37mA    26.93mA    17.87mA
-901mV    15.03mA    21.86mA    16.59mA
-855mV    12.01mA    14.79mA    14.5mA
-763mV    8.448mA    8.108mA    10.89mA
-533mV    2.369mA    2.267mA    3.272mA
-349mV    143.9uA    291.4uA    171.3uA
1.1V      0A         0A         0A
[Ramp]
| variable   typ   min   max
dV/dt_r   0.399/0.162n   0.382/0.205n   0.410/0.128n
dV/dt_f   0.402/0.106n   0.393/0.142n   0.404/90.747p
R_load = 50.000
[Rising Waveform]
R_fixture = 50.000
V_fixture = 0.000
V_fixture_min = 0.000
V_fixture_max = 0.000
|  time   V(typ)   V(min)   V(max)
0s        1.49uV     6.926uV    592.9nV
399ps     -319uV     69.77uV    8.056mV
446ps     -1.831mV   22.31uV    81.72mV
524ps     11.25mV    -1.561mV   357.6mV
634ps     244.7mV    12.4mV     628.3mV
733ps     509.3mV    160.9mV    686.2mV
833ps     629mV      389.7mV    700.9mV
1.023ns   678.9mV    601.3mV    707.3mV
1.387ns   689.5mV    654.7mV    708.8mV
10ns      690.7mV    662mV      708.9mV
[Rising Waveform]
R_fixture = 50.000
V_fixture = 0.550
V_fixture_min = 0.534
V_fixture_max = 0.568
|  time   V(typ)   V(min)   V(max)
0s        214.4mV    206.4mV    229.1mV
405ps     214mV      206.4mV    237.4mV
518ps     226mV      205.7mV    615.3mV
577ps     344mV      206.7mV    802.3mV
649ps     581.1mV    245.7mV    883.5mV
718ps     761.4mV    390mV      906.9mV
788ps     842mV      580.7mV    915.1mV
937ps     885.2mV    801.2mV    919.9mV
1.277ns   895.5mV    860.8mV    921.3mV
10ns      896.5mV    867mV      921.4mV
[Falling Waveform]
R_fixture = 50.000
V_fixture = 0.550
V_fixture_min = 0.534
V_fixture_max = 0.568
|  time   V(typ)   V(min)   V(max)
0s        896.5mV    867mV      921.4mV
387ps     897.3mV    867.1mV    919.6mV
426ps     899.4mV    867.4mV    824.4mV
495ps     891mV      869.5mV    462.5mV
544ps     793.2mV    869.6mV    316.3mV
624ps     431.4mV    831.2mV    250mV
720ps     255.1mV    564.6mV    234.4mV
839ps     223.3mV    275.3mV    230.6mV
1.079ns   215.8mV    213.9mV    229.3mV
10ns      214.4mV    206.4mV    229.1mV
[Falling Waveform]
R_fixture = 50.000
V_fixture = 0.000
V_fixture_min = 0.000
V_fixture_max = 0.000
|  time   V(typ)   V(min)   V(max)
0s        690.7mV    662mV      708.9mV
385ps     692.1mV    662.2mV    705.9mV
423ps     694.4mV    662.9mV    605.3mV
493ps     679.1mV    665.8mV    220.1mV
535ps     579.8mV    665.2mV    90.04mV
609ps     219.9mV    623.3mV    21.14mV
699ps     37.52mV    343.1mV    4.746mV
809ps     6.299mV    57.44mV    1.146mV
999ps     884.7uV    3.892mV    228.8uV
10ns      1.49uV     6.926uV    592.9nV
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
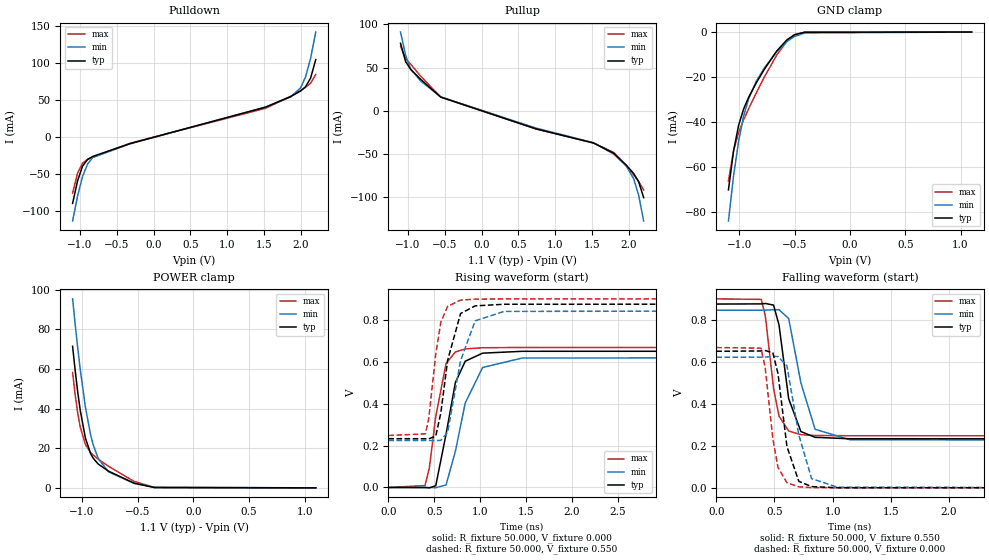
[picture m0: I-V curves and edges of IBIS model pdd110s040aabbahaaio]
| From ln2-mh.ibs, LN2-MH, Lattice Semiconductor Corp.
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|   Model pdd110s040aabbahaaio
[Model] pdd110s040aabbahaaio
| Clamp models do not include dynamic input termination. Please refer to
| the pdd110axxxaabbahaain model for input termination.
Model_type I/O
Polarity   Non-Inverting
Enable   Active-Low
Vinl =  0.700V
Vinh =  0.900V
Vmeas =  0.550V
Cref =  20.000pF
Rref =  50.000
Vref =  0.600V
C_comp   2.000pF   1.500pF   2.500pF
[Temperature Range]   25.000   0.125k   -40.000
[Voltage Range]   1.100V   1.070V   1.130V
[C Comp Corner]
C_comp   2.000pF   1.500pF   2.500pF
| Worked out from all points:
|   slope of the pulldown table from 0 to 0.165 V, typ, clamps not added: 36.9 ohm
|   slope of the pullup table from 0 to 0.165 V, typ, clamps not added: 34 ohm
|   GND clamp passes 1 mA (typ) near -0.49 V on its own axis
|   POWER clamp passes 1 mA (typ) near -0.45 V on its own axis
|   rising waveform, R_fixture 50.000, V_fixture 0.000: 20-80 % time 156ps typ, 200ps min, 128ps max; typ from 0 V to 0.652 V
|   rising waveform, R_fixture 50.000, V_fixture 0.550: 20-80 % time 131ps typ, 164ps min, 108ps max; typ from 0.233 V to 0.878 V
|   falling waveform, R_fixture 50.000, V_fixture 0.550: 20-80 % time 98.6ps typ, 125ps min, 88.3ps max; typ from 0.878 V to 0.233 V
|   falling waveform, R_fixture 50.000, V_fixture 0.000: 20-80 % time 93.6ps typ, 114ps min, 86.2ps max; typ from 0.652 V to 0 V
[Pulldown]
|Voltage   I(typ)   I(min)   I(max)
-1.1V     -89.3mA    -113mA     -75.35mA
-1.032V   -58.62mA   -78.91mA   -48.28mA
-964mV    -38.91mA   -52.75mA   -34.86mA
-896mV    -30mA      -36.13mA   -30.08mA
-828mV    -26.09mA   -27.54mA   -27.12mA
-318mV    -8.7mA     -8.922mA   -8.238mA
1.518V    40.3mA     40.42mA    38.8mA
1.858V    54.6mA     54.02mA    54.72mA
1.994V    62.1mA     66.32mA    62.84mA
2.062V    67.75mA    81.17mA    67.18mA
2.13V     79.49mA    106.1mA    72.58mA
2.2V      104.4mA    141.5mA    84.35mA
[Pullup]
|Voltage   I(typ)   I(min)   I(max)
-1.1V     78.02mA    91.03mA    74.68mA
-1.03V    56.63mA    63.91mA    59.82mA
-962mV    47.88mA    48.19mA    53.86mA
-826mV    36.28mA    34.37mA    39.94mA
-554mV    15.8mA     16.04mA    15.88mA
738mV     -20.84mA   -20.01mA   -20.96mA
1.52V     -37.29mA   -36.91mA   -37.13mA
1.792V    -48.9mA    -49.96mA   -48.18mA
1.962V    -62.6mA    -63.6mA    -63.61mA
2.064V    -72.46mA   -78.42mA   -74.13mA
2.132V    -82.06mA   -97.62mA   -81.67mA
2.2V      -100.4mA   -127.4mA   -91.53mA
[GND_clamp]
|Voltage   I(typ)   I(min)   I(max)
-1.1V     -70.18mA   -84.03mA   -66.29mA
-1.054V   -53.01mA   -64.11mA   -52.8mA
-1.008V   -41.48mA   -48.48mA   -44.7mA
-962mV    -34.13mA   -37.22mA   -38.96mA
-916mV    -28.9mA    -29.49mA   -33.98mA
-847mV    -22.51mA   -21.79mA   -26.95mA
-778mV    -16.79mA   -16.17mA   -20.26mA
-663mV    -8.43mA    -8.709mA   -10.22mA
-571mV    -3.466mA   -4.237mA   -4.094mA
-502mV    -1.18mA    -1.941mA   -1.256mA
-410mV    -105.5uA   -402.4uA   -63.37uA
1.1V      0A         0A         0A
[POWER_clamp]
|Voltage   I(typ)   I(min)   I(max)
-1.085V   71.41mA    95.35mA    58.18mA
-1.062V   59.23mA    82.55mA    46.99mA
-1.039V   48.36mA    70.56mA    37.71mA
-1.016V   38.97mA    59.53mA    30.53mA
-970mV    25.17mA    40.76mA    21.88mA
-924mV    17.37mA    26.93mA    17.87mA
-901mV    15.03mA    21.86mA    16.59mA
-855mV    12.01mA    14.79mA    14.5mA
-763mV    8.448mA    8.108mA    10.89mA
-533mV    2.369mA    2.267mA    3.272mA
-349mV    143.9uA    291.4uA    171.3uA
1.1V      0A         0A         0A
[Ramp]
| variable   typ   min   max
dV/dt_r   0.376/0.157n   0.359/0.200n   0.386/0.128n
dV/dt_f   0.379/0.108n   0.371/0.145n   0.381/92.566p
R_load = 50.000
[Rising Waveform]
R_fixture = 50.000
V_fixture = 0.000
V_fixture_min = 0.000
V_fixture_max = 0.000
|  time   V(typ)   V(min)   V(max)
0s        1.497uV    7.052uV    0V
399ps     -300.7uV   71.63uV    9.145mV
447ps     -1.731mV   15.87uV    95.35mV
516ps     8.418mV    -1.179mV   340mV
628ps     254.9mV    12.17mV    592.9mV
730ps     502.9mV    174mV      648.5mV
837ps     604.1mV    404.1mV    663mV
1.026ns   642.7mV    574mV      668.6mV
1.456ns   651.5mV    619.2mV    669.9mV
10ns      652.2mV    623.7mV    670mV
[Rising Waveform]
R_fixture = 50.000
V_fixture = 0.550
V_fixture_min = 0.534
V_fixture_max = 0.568
|  time   V(typ)   V(min)   V(max)
0s        233.5mV    224.9mV    248.7mV
404ps     233.1mV    225mV      256.6mV
440ps     232.8mV    224.9mV    331.7mV
516ps     245.8mV    224.3mV    638.1mV
571ps     356.1mV    225.5mV    790.6mV
645ps     607.8mV    263.9mV    866.2mV
786ps     832.3mV    606.6mV    896.4mV
945ps     868.9mV    797.4mV    901.1mV
1.261ns   876.6mV    842.4mV    902.2mV
10ns      877.6mV    848.1mV    902.4mV
[Falling Waveform]
R_fixture = 50.000
V_fixture = 0.550
V_fixture_min = 0.534
V_fixture_max = 0.568
|  time   V(typ)   V(min)   V(max)
0s        877.6mV    848.1mV    902.4mV
387ps     878.4mV    848.2mV    899.9mV
422ps     880.2mV    848.5mV    818.3mV
492ps     872.7mV    850.5mV    474.9mV
539ps     778.2mV    850.8mV    342.2mV
622ps     425.4mV    808.5mV    271.6mV
727ps     268.9mV    501.2mV    253.8mV
849ps     241.3mV    279.5mV    250mV
1.149ns   234.3mV    229.5mV    248.8mV
10ns      233.5mV    224.9mV    248.7mV
[Falling Waveform]
R_fixture = 50.000
V_fixture = 0.000
V_fixture_min = 0.000
V_fixture_max = 0.000
|  time   V(typ)   V(min)   V(max)
0s        652.2mV    623.7mV    670mV
384ps     653.6mV    623.9mV    667mV
420ps     655.8mV    624.5mV    574.7mV
486ps     645mV      627.3mV    233.8mV
530ps     546.2mV    627.2mV    98.01mV
607ps     197.3mV    582.5mV    24.05mV
709ps     31.21mV    253mV      4.753mV
819ps     5.965mV    44.01mV    1.145mV
1.043ns   626.9uV    2.639mV    163.2uV
10ns      1.497uV    7.052uV    0V
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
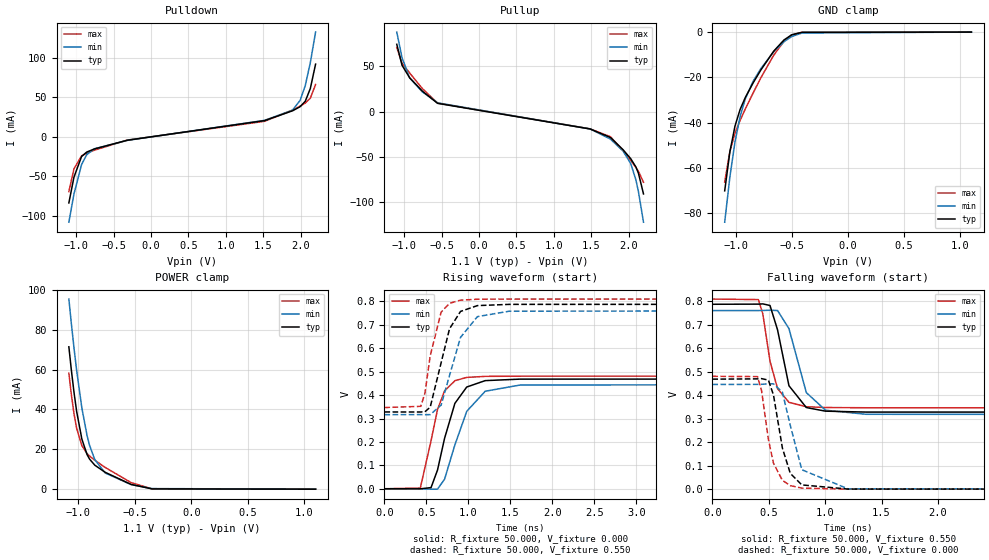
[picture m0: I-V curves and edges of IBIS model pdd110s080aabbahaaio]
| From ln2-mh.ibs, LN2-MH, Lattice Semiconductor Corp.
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|   Model pdd110s080aabbahaaio
[Model] pdd110s080aabbahaaio
| Clamp models do not include dynamic input termination. Please refer to
| the pdd110axxxaabbahaain model for input termination.
Model_type I/O
Polarity   Non-Inverting
Enable   Active-Low
Vinl =  0.700V
Vinh =  0.900V
Vmeas =  0.550V
Cref =  20.000pF
Rref =  50.000
Vref =  0.600V
C_comp   2.000pF   1.500pF   2.500pF
[Temperature Range]   25.000   0.125k   -40.000
[Voltage Range]   1.100V   1.070V   1.130V
[C Comp Corner]
C_comp   2.000pF   1.500pF   2.500pF
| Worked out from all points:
|   slope of the pulldown table from 0 to 0.165 V, typ, clamps not added: 73.8 ohm
|   slope of the pullup table from 0 to 0.165 V, typ, clamps not added: 65.6 ohm
|   GND clamp passes 1 mA (typ) near -0.49 V on its own axis
|   POWER clamp passes 1 mA (typ) near -0.45 V on its own axis
|   rising waveform, R_fixture 50.000, V_fixture 0.000: 20-80 % time 211ps typ, 259ps min, 170ps max; typ from 0 V to 0.469 V
|   rising waveform, R_fixture 50.000, V_fixture 0.550: 20-80 % time 175ps typ, 217ps min, 135ps max; typ from 0.328 V to 0.788 V
|   falling waveform, R_fixture 50.000, V_fixture 0.550: 20-80 % time 125ps typ, 154ps min, 111ps max; typ from 0.788 V to 0.328 V
|   falling waveform, R_fixture 50.000, V_fixture 0.000: 20-80 % time 115ps typ, 132ps min, 105ps max; typ from 0.469 V to 0 V
[Pulldown]
|Voltage   I(typ)   I(min)   I(max)
-1.1V     -83.5mA    -107.8mA   -69.21mA
-1.032V   -51.03mA   -72.35mA   -40.55mA
-930mV    -24.93mA   -35.11mA   -24.05mA
-862mV    -19.36mA   -22.74mA   -20.78mA
-760mV    -15.41mA   -15.16mA   -16.98mA
-318mV    -4.38mA    -4.548mA   -4.125mA
1.518V    20.39mA    20.71mA    19.49mA
1.892V    32.77mA    33.6mA     33.64mA
1.994V    37.99mA    46.04mA    38.71mA
2.062V    44.81mA    64.59mA    42.51mA
2.13V     60.93mA    93.6mA     48.72mA
2.2V      91.63mA    132.1mA    65.98mA
[Pullup]
|Voltage   I(typ)   I(min)   I(max)
-1.1V     74.42mA    87.92mA    70.82mA
-1.03V    51.34mA    59.68mA    53.66mA
-928mV    37.49mA    37.38mA    42.79mA
-758mV    22.74mA    21.95mA    25.6mA
-554mV    9.276mA    9.823mA    9.51mA
1.486V    -19.01mA   -18.96mA   -18.87mA
1.758V    -28.41mA   -30.16mA   -27.6mA
1.928V    -42.03mA   -43.53mA   -42.99mA
2.03V     -51.92mA   -57.35mA   -53.78mA
2.098V    -60.92mA   -75.11mA   -61.47mA
2.132V    -67.74mA   -88.02mA   -65.72mA
2.2V      -90.73mA   -121.9mA   -77.85mA
[GND_clamp]
|Voltage   I(typ)   I(min)   I(max)
-1.1V     -70.16mA   -84.02mA   -66.27mA
-1.054V   -52.99mA   -64.1mA    -52.77mA
-1.008V   -41.47mA   -48.47mA   -44.67mA
-962mV    -34.12mA   -37.21mA   -38.94mA
-916mV    -28.89mA   -29.48mA   -33.96mA
-847mV    -22.5mA    -21.78mA   -26.94mA
-778mV    -16.78mA   -16.17mA   -20.25mA
-663mV    -8.428mA   -8.707mA   -10.22mA
-571mV    -3.466mA   -4.237mA   -4.093mA
-502mV    -1.18mA    -1.94mA    -1.256mA
-410mV    -105.5uA   -402.4uA   -63.37uA
1.1V      0A         0A         0A
[POWER_clamp]
|Voltage   I(typ)   I(min)   I(max)
-1.085V   71.41mA    95.35mA    58.18mA
-1.062V   59.23mA    82.55mA    46.99mA
-1.039V   48.36mA    70.56mA    37.71mA
-1.016V   38.97mA    59.53mA    30.53mA
-970mV    25.17mA    40.76mA    21.88mA
-924mV    17.37mA    26.93mA    17.87mA
-901mV    15.03mA    21.86mA    16.59mA
-855mV    12.01mA    14.79mA    14.5mA
-763mV    8.448mA    8.108mA    10.89mA
-533mV    2.369mA    2.267mA    3.272mA
-349mV    143.9uA    291.4uA    171.3uA
1.1V      0A         0A         0A
[Ramp]
| variable   typ   min   max
dV/dt_r   0.281/0.211n   0.268/0.259n   0.289/0.170n
dV/dt_f   0.266/0.142n   0.261/0.183n   0.264/0.122n
R_load = 50.000
[Rising Waveform]
R_fixture = 50.000
V_fixture = 0.000
V_fixture_min = 0.000
V_fixture_max = 0.000
|  time   V(typ)   V(min)   V(max)
0s        1.577uV    10.97uV    1.615uV
427ps     -294.2uV   230.7uV    2.933mV
555ps     4.992mV    -1.754mV   205mV
632ps     79.88mV    -1.62mV    338.5mV
716ps     215.3mV    40.78mV    417.7mV
839ps     364.7mV    187.5mV    461.6mV
980ps     434.5mV    330.6mV    475.5mV
1.2ns     461.8mV    416.5mV    480mV
1.616ns   468.2mV    443mV      480.8mV
10ns      468.8mV    446.3mV    480.9mV
[Rising Waveform]
R_fixture = 50.000
V_fixture = 0.550
V_fixture_min = 0.534
V_fixture_max = 0.568
|  time   V(typ)   V(min)   V(max)
0s        327.9mV    316.5mV    346.8mV
433ps     327.8mV    316.7mV    352mV
482ps     328.8mV    316.4mV    407.9mV
545ps     348.4mV    316.6mV    567.2mV
675ps     538.3mV    357.2mV    754.3mV
775ps     683.1mV    483.7mV    792mV
906ps     757.3mV    646.5mV    805.5mV
1.107ns   782.2mV    735.1mV    809.4mV
1.487ns   787.4mV    758.3mV    810.1mV
10ns      787.9mV    761mV      810.1mV
[Falling Waveform]
R_fixture = 50.000
V_fixture = 0.550
V_fixture_min = 0.534
V_fixture_max = 0.568
|  time   V(typ)   V(min)   V(max)
0s        787.9mV    761mV      810.1mV
408ps     788.5mV    761.1mV    807.8mV
447ps     789.6mV    761.4mV    747.5mV
511ps     782.8mV    762.5mV    545.5mV
578ps     678.8mV    761.3mV    428.3mV
679ps     440.9mV    684.1mV    370.1mV
833ps     347.8mV    411.6mV    351.3mV
1.003ns   332.4mV    336.4mV    347.9mV
1.363ns   328.5mV    319.1mV    346.9mV
10ns      327.9mV    316.5mV    346.8mV
[Falling Waveform]
R_fixture = 50.000
V_fixture = 0.000
V_fixture_min = 0.000
V_fixture_max = 0.000
|  time   V(typ)   V(min)   V(max)
0s        468.8mV    446.3mV    480.9mV
400ps     470mV      446.5mV    479.6mV
436ps     471.1mV    446.9mV    420.6mV
497ps     464.7mV    448.8mV    210.8mV
542ps     400.9mV    448.9mV    110.4mV
621ps     174.9mV    413.3mV    37.36mV
691ps     67.23mV    271.7mV    15.06mV
793ps     18.14mV    82.81mV    4.411mV
1.203ns   438.9uV    1.317mV    160.8uV
10ns      1.577uV    10.97uV    1.615uV
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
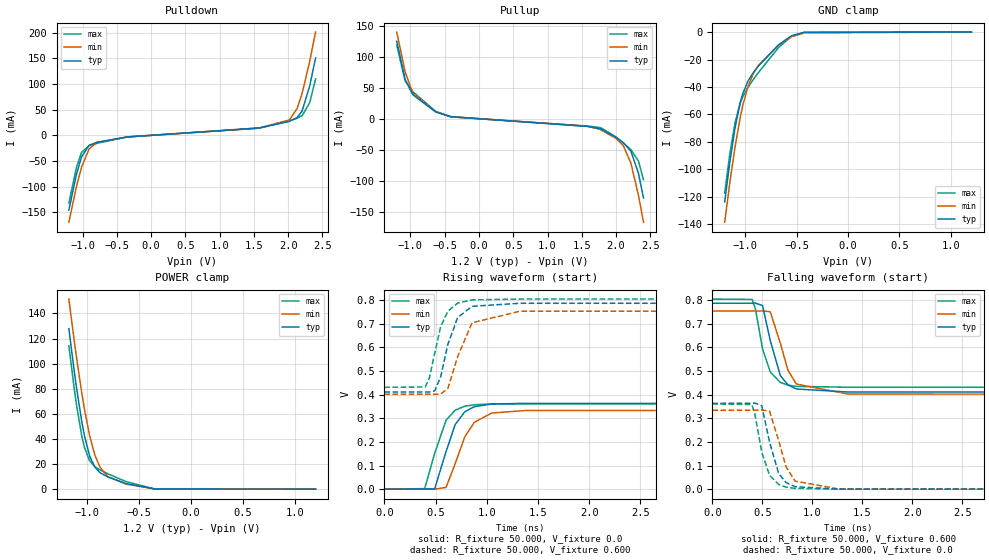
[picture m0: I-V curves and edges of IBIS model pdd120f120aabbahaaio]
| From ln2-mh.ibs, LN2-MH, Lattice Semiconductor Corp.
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|   Model pdd120f120aabbahaaio
[Model] pdd120f120aabbahaaio
| Clamp models do not include dynamic input termination. Please refer to
| the pdd120axxxaabbahaain model for input termination.
Model_type I/O
Polarity   Non-Inverting
Enable   Active-Low
Vinl =  0.800V
Vinh =  1.000V
Vmeas =  0.600V
Cref =  20.000pF
Rref =  50.000
Vref =  0.600V
C_comp   2.000pF   1.500pF   2.500pF
[Temperature Range]   25.000   0.125k   -40.000
[Voltage Range]   1.200V   1.160V   1.240V
[C Comp Corner]
C_comp   2.000pF   1.500pF   2.500pF
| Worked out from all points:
|   slope of the pulldown table from 0 to 0.18 V, typ, clamps not added: 108 ohm
|   slope of the pullup table from 0 to 0.18 V, typ, clamps not added: 110 ohm
|   GND clamp passes 1 mA (typ) near -0.49 V on its own axis
|   POWER clamp passes 1 mA (typ) near -0.45 V on its own axis
|   rising waveform, R_fixture 50.000, V_fixture 0.0: 20-80 % time 163ps typ, 186ps min, 152ps max; typ from 0 V to 0.363 V
|   rising waveform, R_fixture 50.000, V_fixture 0.600: 20-80 % time 140ps typ, 159ps min, 128ps max; typ from 0.411 V to 0.787 V
|   falling waveform, R_fixture 50.000, V_fixture 0.600: 20-80 % time 130ps typ, 148ps min, 121ps max; typ from 0.787 V to 0.411 V
|   falling waveform, R_fixture 50.000, V_fixture 0.0: 20-80 % time 123ps typ, 138ps min, 117ps max; typ from 0.363 V to 0 V
[Pulldown]
|Voltage   I(typ)   I(min)   I(max)
-1.2V     -146.2mA   -169.6mA   -132.4mA
-1.089V   -76.11mA   -100.1mA   -62.42mA
-1.015V   -42.14mA   -62.24mA   -33.47mA
-904mV    -19.52mA   -26.6mA    -20.2mA
-793mV    -13.92mA   -14.05mA   -15.84mA
-349mV    -3.364mA   -3.446mA   -3.218mA
1.575V    14.23mA    14.15mA    13.66mA
2.019V    27.14mA    29.91mA    28.05mA
2.13V     34.19mA    52.06mA    33.31mA
2.204V    47.64mA    81.78mA    38.11mA
2.315V    96.57mA    144.6mA    63.67mA
2.4V      150.6mA    201.2mA    110mA
[Pullup]
|Voltage   I(typ)   I(min)   I(max)
-1.2V     125.9mA    140.7mA    119.4mA
-1.078V   64.1mA     76.51mA    61.81mA
-967mV    39.35mA    41.86mA    44.19mA
-634mV    11.47mA    11.63mA    12.4mA
-412mV    3.743mA    3.771mA    3.422mA
1.586V    -12.11mA   -11.81mA   -11.44mA
1.771V    -15.73mA   -17.27mA   -13.95mA
1.993V    -29.36mA   -30.95mA   -28.52mA
2.104V    -38.42mA   -42.98mA   -38.57mA
2.215V    -51.91mA   -71.07mA   -49.55mA
2.326V    -87.84mA   -123.2mA   -68.05mA
2.4V      -128mA     -167.1mA   -98.35mA
[GND_clamp]
|Voltage   I(typ)   I(min)   I(max)
-1.2V     -123.8mA   -138.6mA   -117.4mA
-1.15V    -94.76mA   -109.7mA   -88.72mA
-1.1V     -70.18mA   -84.03mA   -66.26mA
-1.05V    -51.79mA   -62.58mA   -51.92mA
-1.025V   -45.15mA   -53.74mA   -47.27mA
-975mV    -35.93mA   -40mA      -40.48mA
-925mV    -29.85mA   -30.8mA    -34.94mA
-875mV    -25.01mA   -24.55mA   -29.78mA
-675mV    -9.225mA   -9.408mA   -11.19mA
-550mV    -2.634mA   -3.442mA   -3.058mA
-425mV    -169.7uA   -547.4uA   -117uA
1.2V      0A         0A         0A
[POWER_clamp]
|Voltage   I(typ)   I(min)   I(max)
-1.175V   127.9mA    151.5mA    114.3mA
-1.125V   95.1mA     119.3mA    81.28mA
-1.1V     80mA       104.2mA    66.46mA
-1.05V    53.45mA    76.25mA    42.06mA
-1.025V   42.52mA    63.79mA    33.25mA
-975mV    26.42mA    42.64mA    22.65mA
-925mV    17.53mA    27.24mA    17.97mA
-875mV    13.15mA    17.46mA    15.37mA
-800mV    9.709mA    10.06mA    12.3mA
-625mV    4.479mA    4.015mA    6.021mA
-350mV    147.7uA    296.5uA    176.7uA
1.2V      0A         0A         0A
[Ramp]
| variable   typ   min   max
dV/dt_r   0.218/0.163n   0.200/0.186n   0.217/0.152n
dV/dt_f   0.226/0.144n   0.215/0.170n   0.225/0.132n
R_load = 50.000
[Rising Waveform]
R_fixture= 50.000
V_fixture= 0.0
V_fixture_min= 0.0
V_fixture_max= 0.0
|time   V(typ)   V(min)   V(max)
0s        1.991uV    10.66uV    896.8nV
393ps     225.8uV    129.8uV    2.314mV
490ps     1.098mV    -22.6uV    151mV
602ps     159.5mV    7.393mV    292.2mV
691ps     273.5mV    108.4mV    334.2mV
785ps     327.8mV    221.8mV    351.1mV
877ps     349mV      282.8mV    357.2mV
1.047ns   360.5mV    322.1mV    360.2mV
1.377ns   363mV      332.8mV    360.9mV
10ns      363.2mV    333.6mV    360.9mV
[Rising Waveform]
R_fixture= 50.000
V_fixture= 0.600
V_fixture_min= 0.583
V_fixture_max= 0.619
|time   V(typ)   V(min)   V(max)
0s        411mV      401.5mV    431.1mV
398ps     411.1mV    401.6mV    432.3mV
440ps     411.1mV    401.7mV    472.7mV
491ps     416.4mV    401.5mV    575.8mV
549ps     475.3mV    402.2mV    687.8mV
620ps     613.9mV    426.6mV    753.5mV
715ps     726.4mV    560.7mV    787.4mV
856ps     773.8mV    704.4mV    800.9mV
1.325ns   786.6mV    752.9mV    804.4mV
10ns      786.8mV    753.6mV    804.4mV
[Falling Waveform]
R_fixture= 50.000
V_fixture= 0.600
V_fixture_min= 0.583
V_fixture_max= 0.619
|time   V(typ)   V(min)   V(max)
0s        786.8mV    753.6mV    804.4mV
398ps     787mV      753.6mV    802.9mV
430ps     787.6mV    753.6mV    764.2mV
502ps     776.8mV    754.4mV    593.1mV
579ps     629.2mV    750.6mV    495.8mV
680ps     480.4mV    616.9mV    451.7mV
756ps     441.3mV    503.3mV    440.2mV
840ps     423.8mV    444.8mV    435mV
1.357ns   411.2mV    402.4mV    431.2mV
10ns      411mV      401.5mV    431.1mV
[Falling Waveform]
R_fixture= 50.000
V_fixture= 0.0
V_fixture_min= 0.0
V_fixture_max= 0.0
|time   V(typ)   V(min)   V(max)
0s        363.1mV    333.6mV    360.9mV
395ps     363.7mV    333.6mV    358.1mV
427ps     364.3mV    333.7mV    314.4mV
494ps     352.9mV    334.8mV    156.3mV
572ps     199.1mV    329.8mV    58.87mV
663ps     66.29mV    205.6mV    20.01mV
736ps     28.34mV    95.28mV    8.738mV
827ps     10.35mV    34.08mV    3.265mV
1.267ns   234.9uV    632.7uV    92.37uV
10ns      2.007uV    10.68uV    917.3nV
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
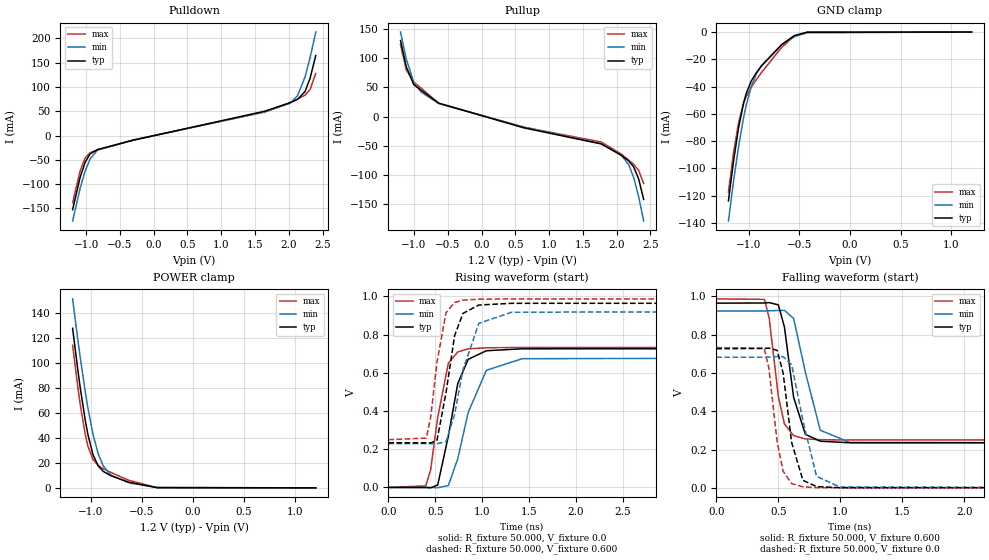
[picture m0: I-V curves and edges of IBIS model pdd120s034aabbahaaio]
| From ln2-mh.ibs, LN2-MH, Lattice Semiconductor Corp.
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|   Model pdd120s034aabbahaaio
[Model] pdd120s034aabbahaaio
| Clamp models do not include dynamic input termination. Please refer to
| the pdd120axxxaabbahaain model for input termination.
Model_type I/O
Polarity   Non-Inverting
Enable   Active-Low
Vinl =  0.800V
Vinh =  1.000V
Vmeas =  0.600V
Cref =  20.000pF
Rref =  50.000
Vref =  0.600V
C_comp   2.000pF   1.500pF   2.500pF
[Temperature Range]   25.000   0.125k   -40.000
[Voltage Range]   1.200V   1.160V   1.240V
[C Comp Corner]
C_comp   2.000pF   1.500pF   2.500pF
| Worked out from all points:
|   slope of the pulldown table from 0 to 0.18 V, typ, clamps not added: 31.9 ohm
|   slope of the pullup table from 0 to 0.18 V, typ, clamps not added: 32.3 ohm
|   GND clamp passes 1 mA (typ) near -0.49 V on its own axis
|   POWER clamp passes 1 mA (typ) near -0.45 V on its own axis
|   rising waveform, R_fixture 50.000, V_fixture 0.0: 20-80 % time 162ps typ, 220ps min, 130ps max; typ from 0 V to 0.727 V
|   rising waveform, R_fixture 50.000, V_fixture 0.600: 20-80 % time 138ps typ, 183ps min, 112ps max; typ from 0.234 V to 0.965 V
|   falling waveform, R_fixture 50.000, V_fixture 0.600: 20-80 % time 95.8ps typ, 124ps min, 85.2ps max; typ from 0.965 V to 0.234 V
|   falling waveform, R_fixture 50.000, V_fixture 0.0: 20-80 % time 90ps typ, 113ps min, 82.3ps max; typ from 0.726 V to 0 V
[Pulldown]
|Voltage   I(typ)   I(min)   I(max)
-1.2V     -152.5mA   -175.8mA   -138.2mA
-1.089V   -86.16mA   -108.8mA   -72.94mA
-1.015V   -55.07mA   -73.23mA   -46.18mA
-941mV    -37.7mA    -48.09mA   -35.29mA
-830mV    -28.79mA   -29.76mA   -29.55mA
-312mV    -9.836mA   -9.775mA   -9.292mA
1.649V    50.26mA    48.96mA    48.52mA
2.019V    67.58mA    66.43mA    67.78mA
2.13V     74.55mA    81.89mA    74.87mA
2.241V    90.47mA    120.4mA    83.09mA
2.315V    117.4mA    159.6mA    94.54mA
2.4V      164.7mA    213mA      127.8mA
[Pullup]
|Voltage   I(typ)   I(min)   I(max)
-1.2V     130.2mA    144.8mA    123.2mA
-1.115V   85.35mA    98.92mA    80.25mA
-1.004V   55.01mA    58.49mA    59.21mA
-893mV    45.11mA    42.04mA    48.75mA
-634mV    23.16mA    22.56mA    22.95mA
624mV     -18.94mA   -17.62mA   -17.91mA
1.771V    -46.49mA   -45.93mA   -43.19mA
2.067V    -65.74mA   -65.68mA   -63.64mA
2.178V    -75.57mA   -81.91mA   -74.02mA
2.252V    -85.75mA   -103.9mA   -81.5mA
2.326V    -106.5mA   -137mA     -91.79mA
2.4V      -141.4mA   -178.3mA   -114.3mA
[GND_clamp]
|Voltage   I(typ)   I(min)   I(max)
-1.2V     -123.9mA   -138.6mA   -117.5mA
-1.15V    -94.79mA   -109.7mA   -88.79mA
-1.1V     -70.21mA   -84.06mA   -66.34mA
-1.05V    -51.83mA   -62.6mA    -51.99mA
-1.025V   -45.19mA   -53.76mA   -47.33mA
-975mV    -35.96mA   -40.02mA   -40.53mA
-925mV    -29.87mA   -30.82mA   -34.98mA
-875mV    -25.03mA   -24.57mA   -29.81mA
-675mV    -9.23mA    -9.413mA   -11.2mA
-550mV    -2.635mA   -3.443mA   -3.06mA
-425mV    -169.7uA   -547.4uA   -117uA
1.2V      0A         0A         0A
[POWER_clamp]
|Voltage   I(typ)   I(min)   I(max)
-1.175V   127.9mA    151.5mA    114.3mA
-1.125V   95.1mA     119.3mA    81.28mA
-1.1V     80mA       104.2mA    66.46mA
-1.05V    53.45mA    76.25mA    42.06mA
-1.025V   42.52mA    63.79mA    33.25mA
-975mV    26.42mA    42.64mA    22.65mA
-925mV    17.53mA    27.24mA    17.97mA
-875mV    13.15mA    17.46mA    15.37mA
-800mV    9.709mA    10.06mA    12.3mA
-625mV    4.479mA    4.015mA    6.021mA
-350mV    147.7uA    296.5uA    176.7uA
1.2V      0A         0A         0A
[Ramp]
| variable   typ   min   max
dV/dt_r   0.436/0.163n   0.409/0.220n   0.440/0.130n
dV/dt_f   0.439/0.107n   0.421/0.144n   0.444/90.831p
R_load = 50.000
[Rising Waveform]
R_fixture= 50.000
V_fixture= 0.0
V_fixture_min= 0.0
V_fixture_max= 0.0
|time   V(typ)   V(min)   V(max)
0s        1.029uV    5.623uV    470.9nV
399ps     -309.1uV   65.22uV    7.895mV
451ps     -2.092mV   -18.67uV   93.1mV
526ps     12.76mV    -1.594mV   365.8mV
640ps     269.7mV    10.19mV    650.6mV
740ps     543.6mV    149.8mV    709.4mV
851ps     670.5mV    392.5mV    725.2mV
1.045ns   715.4mV    613mV      731.1mV
1.426ns   725.5mV    673.8mV    732.5mV
10ns      726.5mV    682.1mV    732.6mV
[Rising Waveform]
R_fixture= 50.000
V_fixture= 0.600
V_fixture_min= 0.583
V_fixture_max= 0.619
|time   V(typ)   V(min)   V(max)
0s        233.9mV    229.5mV    249.7mV
405ps     233.5mV    229.6mV    258.3mV
452ps     232.9mV    229.4mV    370.6mV
519ps     247.3mV    228.9mV    657.9mV
615ps     496.5mV    240.2mV    914.8mV
706ps     793.9mV    381.7mV    967.6mV
795ps     910.7mV    615.5mV    980.2mV
965ps     954.7mV    858.7mV    985.5mV
1.315ns   963.6mV    917.1mV    986.8mV
10ns      964.5mV    923.8mV    986.9mV
[Falling Waveform]
R_fixture= 50.000
V_fixture= 0.600
V_fixture_min= 0.583
V_fixture_max= 0.619
|time   V(typ)   V(min)   V(max)
0s        964.5mV    923.8mV    986.9mV
389ps     965.4mV    924mV      984.2mV
427ps     967.4mV    924.2mV    886mV
501ps     955.5mV    926.5mV    475.8mV
550ps     839.3mV    926.6mV    333.8mV
624ps     472.6mV    884.7mV    272.4mV
719ps     279.1mV    603.1mV    255.5mV
839ps     243.5mV    300.8mV    251.3mV
1.079ns   235.5mV    237mV      249.9mV
10ns      233.9mV    229.5mV    249.7mV
[Falling Waveform]
R_fixture= 50.000
V_fixture= 0.0
V_fixture_min= 0.0
V_fixture_max= 0.0
|time   V(typ)   V(min)   V(max)
0s        726.5mV    682.1mV    732.6mV
386ps     728mV      682.3mV    729.7mV
424ps     730.2mV    682.9mV    626.9mV
491ps     718mV      685.6mV    240.5mV
539ps     600.4mV    685.1mV    86.72mV
608ps     237.4mV    643.7mV    22.56mV
699ps     39.37mV    350.6mV    5.012mV
809ps     6.611mV    60.21mV    1.209mV
999ps     920.5uV    3.889mV    228.3uV
10ns      1.042uV    5.628uV    489nV
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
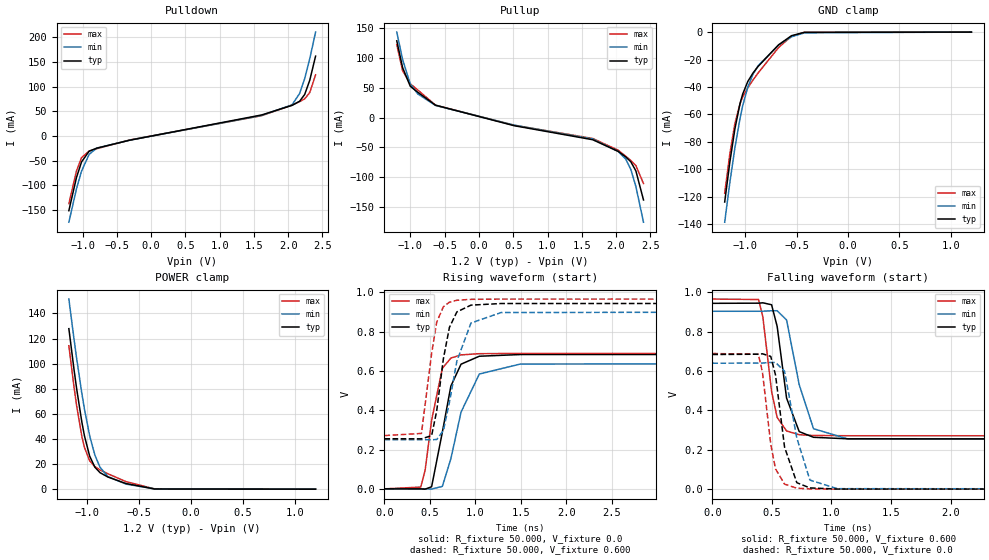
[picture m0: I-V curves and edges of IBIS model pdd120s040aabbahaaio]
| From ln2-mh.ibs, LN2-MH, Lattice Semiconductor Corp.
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|   Model pdd120s040aabbahaaio
[Model] pdd120s040aabbahaaio
| Clamp models do not include dynamic input termination. Please refer to
| the pdd120axxxaabbahaain model for input termination.
Model_type I/O
Polarity   Non-Inverting
Enable   Active-Low
Vinl =  0.800V
Vinh =  1.000V
Vmeas =  0.600V
Cref =  20.000pF
Rref =  50.000
Vref =  0.600V
C_comp   2.000pF   1.500pF   2.500pF
[Temperature Range]   25.000   0.125k   -40.000
[Voltage Range]   1.200V   1.160V   1.240V
[C Comp Corner]
C_comp   2.000pF   1.500pF   2.500pF
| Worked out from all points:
|   slope of the pulldown table from 0 to 0.18 V, typ, clamps not added: 36.9 ohm
|   slope of the pullup table from 0 to 0.18 V, typ, clamps not added: 37.3 ohm
|   GND clamp passes 1 mA (typ) near -0.49 V on its own axis
|   POWER clamp passes 1 mA (typ) near -0.45 V on its own axis
|   rising waveform, R_fixture 50.000, V_fixture 0.0: 20-80 % time 158ps typ, 212ps min, 130ps max; typ from 0 V to 0.684 V
|   rising waveform, R_fixture 50.000, V_fixture 0.600: 20-80 % time 132ps typ, 177ps min, 109ps max; typ from 0.255 V to 0.943 V
|   falling waveform, R_fixture 50.000, V_fixture 0.600: 20-80 % time 98ps typ, 127ps min, 88ps max; typ from 0.943 V to 0.255 V
|   falling waveform, R_fixture 50.000, V_fixture 0.0: 20-80 % time 92.3ps typ, 115ps min, 85.9ps max; typ from 0.684 V to 0 V
[Pulldown]
|Voltage   I(typ)   I(min)   I(max)
-1.2V     -151.2mA   -174.5mA   -137mA
-1.089V   -84.13mA   -107mA     -70.86mA
-1.015V   -52.53mA   -71.04mA   -43.74mA
-904mV    -30.7mA    -37.12mA   -30.5mA
-793mV    -24.67mA   -24.52mA   -25.71mA
-312mV    -8.528mA   -8.485mA   -8.073mA
1.612V    42.52mA    41.43mA    41.08mA
2.056V    61.9mA     63mA       62.51mA
2.167V    70.28mA    86.13mA    69.41mA
2.241V    84.04mA    116.1mA    75.18mA
2.315V    112.8mA    156.3mA    87.92mA
2.4V      161.6mA    210.3mA    123.8mA
[Pullup]
|Voltage   I(typ)   I(min)   I(max)
-1.2V     129.2mA    143.9mA    122.4mA
-1.115V   84.09mA    97.72mA    79.07mA
-1.004V   52.92mA    56.84mA    57.08mA
-893mV    42.55mA    39.83mA    46.42mA
-634mV    20.9mA     20.43mA    20.94mA
513mV     -13.58mA   -12.62mA   -12.84mA
1.66V     -37.19mA   -35.96mA   -35.08mA
2.03V     -56.8mA    -56.78mA   -54.77mA
2.141V    -66.06mA   -69.74mA   -64.94mA
2.215V    -74.23mA   -87.19mA   -72.14mA
2.289V    -89.63mA   -115.9mA   -80.62mA
2.4V      -138.5mA   -175.9mA   -110.9mA
[GND_clamp]
|Voltage   I(typ)   I(min)   I(max)
-1.2V     -123.9mA   -138.6mA   -117.5mA
-1.15V    -94.79mA   -109.7mA   -88.79mA
-1.1V     -70.21mA   -84.05mA   -66.33mA
-1.05V    -51.83mA   -62.6mA    -51.98mA
-1.025V   -45.19mA   -53.76mA   -47.33mA
-975mV    -35.96mA   -40.02mA   -40.52mA
-925mV    -29.87mA   -30.81mA   -34.98mA
-875mV    -25.03mA   -24.57mA   -29.81mA
-675mV    -9.229mA   -9.413mA   -11.2mA
-550mV    -2.635mA   -3.442mA   -3.059mA
-425mV    -169.7uA   -547.4uA   -117uA
1.2V      0A         0A         0A
[POWER_clamp]
|Voltage   I(typ)   I(min)   I(max)
-1.175V   127.9mA    151.5mA    114.3mA
-1.125V   95.1mA     119.3mA    81.28mA
-1.1V     80mA       104.2mA    66.46mA
-1.05V    53.45mA    76.25mA    42.06mA
-1.025V   42.52mA    63.79mA    33.25mA
-975mV    26.42mA    42.64mA    22.65mA
-925mV    17.53mA    27.24mA    17.97mA
-875mV    13.15mA    17.46mA    15.37mA
-800mV    9.709mA    10.06mA    12.3mA
-625mV    4.479mA    4.015mA    6.021mA
-350mV    147.7uA    296.5uA    176.7uA
1.2V      0A         0A         0A
[Ramp]
| variable   typ   min   max
dV/dt_r   0.410/0.159n   0.384/0.213n   0.413/0.130n
dV/dt_f   0.414/0.109n   0.397/0.147n   0.418/92.946p
R_load = 50.000
[Rising Waveform]
R_fixture= 50.000
V_fixture= 0.0
V_fixture_min= 0.0
V_fixture_max= 0.0
|time   V(typ)   V(min)   V(max)
0s        1.143uV    6.223uV    521.7nV
399ps     -290.3uV   67.49uV    8.882mV
447ps     -1.674mV   15.5uV     92.19mV
519ps     10.64mV    -1.203mV   348.9mV
637ps     287.8mV    12.42mV    613.1mV
731ps     522.9mV    153.4mV    665mV
843ps     634.1mV    390.5mV    681.3mV
1.044ns   674.4mV    584mV      687.4mV
1.493ns   683mV      634.6mV    688.6mV
10ns      683.6mV    639.6mV    688.7mV
[Rising Waveform]
R_fixture= 50.000
V_fixture= 0.600
V_fixture_min= 0.583
V_fixture_max= 0.619
|time   V(typ)   V(min)   V(max)
0s        254.7mV    249.8mV    271mV
407ps     254.3mV    249.9mV    281.7mV
519ps     270.5mV    249.3mV    688.2mV
575ps     396.4mV    251.2mV    848mV
649ps     662.8mV    297.2mV    926.4mV
715ps     821.2mV    439.9mV    949.3mV
797ps     899.9mV    650.2mV    959.1mV
952ps     934.3mV    843.3mV    963.8mV
1.283ns   942.5mV    896.6mV    965mV
10ns      943.4mV    903.1mV    965.2mV
[Falling Waveform]
R_fixture= 50.000
V_fixture= 0.600
V_fixture_min= 0.583
V_fixture_max= 0.619
|time   V(typ)   V(min)   V(max)
0s        943.4mV    903.1mV    965.1mV
388ps     944.3mV    903.2mV    962.8mV
424ps     946.1mV    903.5mV    874mV
497ps     936.2mV    905.6mV    496.4mV
544ps     826.2mV    905.9mV    364mV
623ps     462.2mV    858.7mV    295.4mV
729ps     292.3mV    530.3mV    276.5mV
849ps     263.3mV    306.8mV    272.5mV
1.139ns   255.6mV    254.7mV    271.2mV
10ns      254.7mV    249.8mV    271mV
[Falling Waveform]
R_fixture= 50.000
V_fixture= 0.0
V_fixture_min= 0.0
V_fixture_max= 0.0
|time   V(typ)   V(min)   V(max)
0s        683.6mV    639.6mV    688.7mV
386ps     685.2mV    639.8mV    684.7mV
421ps     687.2mV    640.4mV    592.1mV
490ps     673.9mV    643.2mV    227.8mV
530ps     579.8mV    643.2mV    103.1mV
606ps     213.4mV    598.8mV    25.61mV
709ps     32.79mV    259.6mV    5.015mV
819ps     6.261mV    46.09mV    1.209mV
1.049ns   624.4uV    2.5mV      154.3uV
10ns      1.158uV    6.231uV    540.3nV
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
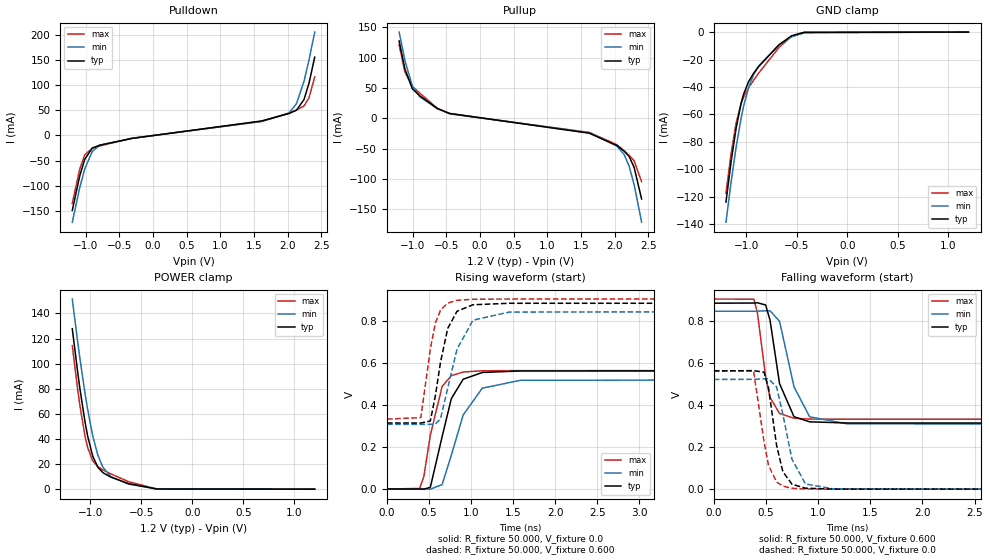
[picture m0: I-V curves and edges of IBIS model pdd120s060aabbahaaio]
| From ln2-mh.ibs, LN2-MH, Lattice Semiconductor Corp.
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|   Model pdd120s060aabbahaaio
[Model] pdd120s060aabbahaaio
| Clamp models do not include dynamic input termination. Please refer to
| the pdd120axxxaabbahaain model for input termination.
Model_type I/O
Polarity   Non-Inverting
Enable   Active-Low
Vinl =  0.800V
Vinh =  1.000V
Vmeas =  0.600V
Cref =  20.000pF
Rref =  50.000
Vref =  0.600V
C_comp   2.000pF   1.500pF   2.500pF
[Temperature Range]   25.000   0.125k   -40.000
[Voltage Range]   1.200V   1.160V   1.240V
[C Comp Corner]
C_comp   2.000pF   1.500pF   2.500pF
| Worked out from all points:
|   slope of the pulldown table from 0 to 0.18 V, typ, clamps not added: 54.8 ohm
|   slope of the pullup table from 0 to 0.18 V, typ, clamps not added: 55.5 ohm
|   GND clamp passes 1 mA (typ) near -0.49 V on its own axis
|   POWER clamp passes 1 mA (typ) near -0.45 V on its own axis
|   rising waveform, R_fixture 50.000, V_fixture 0.0: 20-80 % time 191ps typ, 255ps min, 156ps max; typ from 0 V to 0.562 V
|   rising waveform, R_fixture 50.000, V_fixture 0.600: 20-80 % time 158ps typ, 212ps min, 127ps max; typ from 0.314 V to 0.884 V
|   falling waveform, R_fixture 50.000, V_fixture 0.600: 20-80 % time 116ps typ, 151ps min, 102ps max; typ from 0.884 V to 0.314 V
|   falling waveform, R_fixture 50.000, V_fixture 0.0: 20-80 % time 108ps typ, 135ps min, 99.9ps max; typ from 0.562 V to 0 V
[Pulldown]
|Voltage   I(typ)   I(min)   I(max)
-1.2V     -148.4mA   -171.8mA   -134.5mA
-1.089V   -79.94mA   -103.4mA   -66.48mA
-1.015V   -47.23mA   -66.49mA   -38.54mA
-904mV    -25.09mA   -31.81mA   -25.32mA
-793mV    -19.28mA   -19.26mA   -20.76mA
-312mV    -5.751mA   -5.75mA    -5.442mA
1.612V    28.72mA    28.16mA    27.68mA
2.019V    43.56mA    44.45mA    44.25mA
2.13V     50.29mA    63.23mA    50.23mA
2.241V    71.16mA    107.5mA    58.54mA
2.315V    103.7mA    149.5mA    74.75mA
2.4V      155.2mA    204.8mA    116mA
[Pullup]
|Voltage   I(typ)   I(min)   I(max)
-1.2V     127.4mA    142mA      120.8mA
-1.115V   81.53mA    95.42mA    76.65mA
-1.004V   48.67mA    53.5mA     52.62mA
-893mV    37.23mA    35.31mA    41.49mA
-634mV    16.2mA     16.04mA    16.68mA
-449mV    8.028mA    7.949mA    7.359mA
1.623V    -24.49mA   -23.7mA    -23.12mA
2.03V     -44.47mA   -45.37mA   -43.22mA
2.141V    -53.9mA    -59.47mA   -53.46mA
2.215V    -62.82mA   -78.71mA   -60.77mA
2.289V    -80.43mA   -109.2mA   -69.86mA
2.4V      -132.7mA   -171mA     -104.2mA
[GND_clamp]
|Voltage   I(typ)   I(min)   I(max)
-1.2V     -123.9mA   -138.6mA   -117.5mA
-1.15V    -94.78mA   -109.7mA   -88.79mA
-1.1V     -70.2mA    -84.05mA   -66.33mA
-1.05V    -51.82mA   -62.6mA    -51.97mA
-1.025V   -45.18mA   -53.76mA   -47.32mA
-975mV    -35.95mA   -40.02mA   -40.51mA
-925mV    -29.87mA   -30.81mA   -34.97mA
-875mV    -25.02mA   -24.56mA   -29.8mA
-675mV    -9.228mA   -9.412mA   -11.19mA
-550mV    -2.634mA   -3.442mA   -3.059mA
-425mV    -169.7uA   -547.4uA   -117uA
1.2V      0A         0A         0A
[POWER_clamp]
|Voltage   I(typ)   I(min)   I(max)
-1.175V   127.9mA    151.5mA    114.3mA
-1.125V   95.1mA     119.3mA    81.28mA
-1.1V     80mA       104.2mA    66.46mA
-1.05V    53.45mA    76.25mA    42.06mA
-1.025V   42.52mA    63.79mA    33.25mA
-975mV    26.42mA    42.64mA    22.65mA
-925mV    17.53mA    27.24mA    17.97mA
-875mV    13.15mA    17.46mA    15.37mA
-800mV    9.709mA    10.06mA    12.3mA
-625mV    4.479mA    4.015mA    6.021mA
-350mV    147.7uA    296.5uA    176.7uA
1.2V      0A         0A         0A
[Ramp]
| variable   typ   min   max
dV/dt_r   0.337/0.192n   0.313/0.255n   0.338/0.157n
dV/dt_f   0.343/0.133n   0.328/0.184n   0.344/0.106n
R_load = 50.000
[Rising Waveform]
R_fixture= 50.000
V_fixture= 0.0
V_fixture_min= 0.0
V_fixture_max= 0.0
|time   V(typ)   V(min)   V(max)
0s        1.465uV    7.91uV     665.2nV
387ps     -61.4uV    68.67uV    2.486mV
437ps     -912.6uV   65.15uV    57.4mV
515ps     7.77mV     -873.1uV   256.1mV
655ps     248.6mV    20.79mV    487.9mV
765ps     430.3mV    161.1mV    539.1mV
905ps     522mV      351.8mV    556.6mV
1.132ns   554.2mV    479.5mV    562.2mV
1.585ns   561.5mV    516.9mV    563.2mV
10ns      562.1mV    521.7mV    563.3mV
[Rising Waveform]
R_fixture= 50.000
V_fixture= 0.600
V_fixture_min= 0.583
V_fixture_max= 0.619
|time   V(typ)   V(min)   V(max)
0s        314mV      307.6mV    332.3mV
402ps     313.7mV    307.6mV    339.5mV
515ps     323.6mV    307.3mV    665.3mV
575ps     443.5mV    309.2mV    789.6mV
636ps     603mV      333.6mV    850.5mV
722ps     763.8mV    480.1mV    884.3mV
832ps     845.5mV    665mV      897.5mV
1.022ns   876.4mV    803mV      902.4mV
1.452ns   883.4mV    841.6mV    903.5mV
10ns      883.9mV    845.6mV    903.5mV
[Falling Waveform]
R_fixture= 50.000
V_fixture= 0.600
V_fixture_min= 0.583
V_fixture_max= 0.619
|time   V(typ)   V(min)   V(max)
0s        883.9mV    845.6mV    903.5mV
384ps     884.6mV    845.6mV    902.7mV
417ps     886mV      845.9mV    840.8mV
497ps     875.3mV    847.8mV    532.4mV
539ps     802.7mV    847.7mV    436.1mV
630ps     501.6mV    798.2mV    359.8mV
769ps     344.1mV    486.1mV    336.9mV
919ps     320.1mV    343.6mV    333.2mV
1.279ns   314.5mV    310.6mV    332.3mV
10ns      314mV      307.6mV    332.3mV
[Falling Waveform]
R_fixture= 50.000
V_fixture= 0.0
V_fixture_min= 0.0
V_fixture_max= 0.0
|time   V(typ)   V(min)   V(max)
0s        562mV      521.7mV    563.2mV
381ps     563.4mV    521.8mV    561.1mV
481ps     556.1mV    524.7mV    227mV
524ps     481.9mV    524.8mV    113.6mV
602ps     207.2mV    485.6mV    34mV
662ps     83.05mV    355.7mV    14.3mV
749ps     23.61mV    142.6mV    4.45mV
879ps     4.564mV    24.65mV    955.9uV
1.149ns   393.2uV    1.543mV    90.73uV
10ns      1.484uV    7.927uV    686.9nV
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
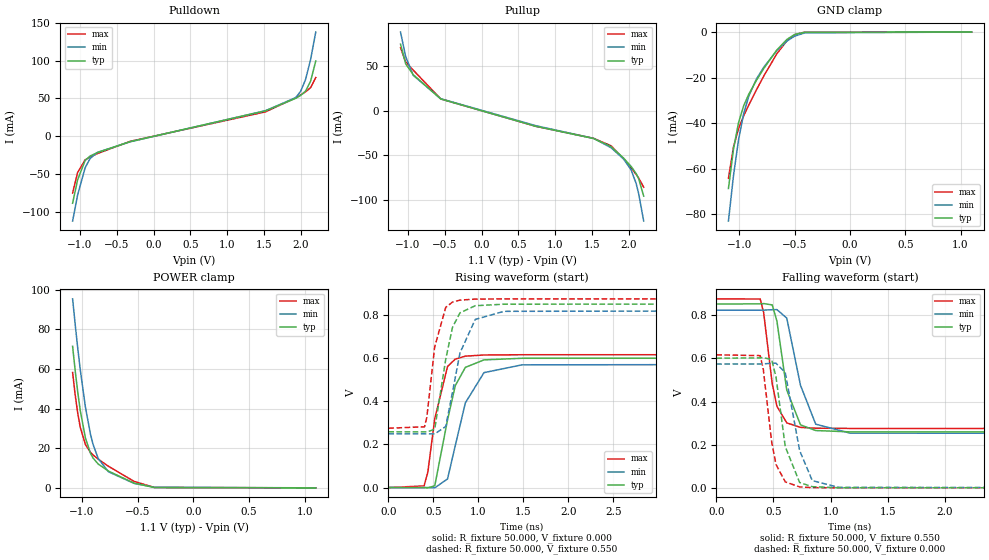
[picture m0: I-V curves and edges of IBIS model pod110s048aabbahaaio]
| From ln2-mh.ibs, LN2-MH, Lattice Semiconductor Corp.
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|   Model pod110s048aabbahaaio
[Model] pod110s048aabbahaaio
| Clamp models do not include dynamic input termination. Please refer to
| the pod110axxxaabbahaain model for input termination.
Model_type I/O
Polarity   Non-Inverting
Enable   Active-Low
Vinl =  0.700V
Vinh =  0.900V
Vmeas =  0.550V
Cref =  20.000pF
Rref =  50.000
Vref =  0.600V
C_comp   2.000pF   1.500pF   2.500pF
[Temperature Range]   25.000   0.125k   -40.000
[Voltage Range]   1.100V   1.070V   1.130V
[C Comp Corner]
C_comp   2.000pF   1.500pF   2.500pF
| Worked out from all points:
|   slope of the pulldown table from 0 to 0.165 V, typ, clamps not added: 44.4 ohm
|   slope of the pullup table from 0 to 0.165 V, typ, clamps not added: 41 ohm
|   GND clamp passes 1 mA (typ) near -0.50 V on its own axis
|   POWER clamp passes 1 mA (typ) near -0.45 V on its own axis
|   rising waveform, R_fixture 50.000, V_fixture 0.000: 20-80 % time 166ps typ, 212ps min, 135ps max; typ from 0 V to 0.601 V
|   rising waveform, R_fixture 50.000, V_fixture 0.550: 20-80 % time 140ps typ, 176ps min, 112ps max; typ from 0.259 V to 0.853 V
|   falling waveform, R_fixture 50.000, V_fixture 0.550: 20-80 % time 106ps typ, 138ps min, 93.2ps max; typ from 0.853 V to 0.259 V
|   falling waveform, R_fixture 50.000, V_fixture 0.000: 20-80 % time 100ps typ, 122ps min, 91.2ps max; typ from 0.601 V to 0 V
[Pulldown]
|Voltage   I(typ)   I(min)   I(max)
-1.1V     -88.71mA   -112.2mA   -75.25mA
-1.032V   -57.76mA   -77.86mA   -48.02mA
-930mV    -32.17mA   -41.77mA   -31.26mA
-862mV    -26.22mA   -29.4mA    -27.47mA
-760mV    -21.58mA   -21.29mA   -22.9mA
-318mV    -7.228mA   -7.436mA   -6.822mA
1.518V    33.49mA    33.69mA    32.15mA
1.926V    49.94mA    50.87mA    50.64mA
1.994V    53.77mA    59.12mA    54.52mA
2.062V    59.67mA    75.04mA    58.65mA
2.13V     72.64mA    101.3mA    64.17mA
2.2V      99.43mA    137.7mA    77.46mA
[Pullup]
|Voltage   I(typ)   I(min)   I(max)
-1.1V     75.12mA    88.71mA    71.1mA
-1.03V    52.9mA     61.03mA    55.16mA
-928mV    40.8mA     40.05mA    45.89mA
-554mV    13.4mA     13.73mA    13.48mA
738mV     -17.31mA   -16.65mA   -17.36mA
1.52V     -31.01mA   -30.85mA   -30.8mA
1.758V    -40.08mA   -41.42mA   -39.19mA
1.928V    -53.14mA   -54.12mA   -53.83mA
2.03V     -62.48mA   -66.36mA   -64.17mA
2.098V    -70.48mA   -81.7mA    -71.47mA
2.132V    -76.24mA   -93.08mA   -75.4mA
2.2V      -95.76mA   -123.8mA   -85.78mA
[GND_clamp]
|Voltage   I(typ)   I(min)   I(max)
-1.1V     -68.65mA   -82.91mA   -64.16mA
-1.054V   -51.26mA   -62.87mA   -50.37mA
-1.008V   -39.63mA   -47.13mA   -42.26mA
-962mV    -32.34mA   -35.82mA   -36.73mA
-916mV    -27.28mA   -28.13mA   -32.02mA
-847mV    -21.22mA   -20.63mA   -25.4mA
-778mV    -15.81mA   -15.27mA   -19.09mA
-663mV    -7.926mA   -8.201mA   -9.607mA
-571mV    -3.246mA   -3.982mA   -3.828mA
-502mV    -1.097mA   -1.819mA   -1.164mA
-410mV    -96.97uA   -374.9uA   -57.53uA
1.1V      0A         0A         0A
[POWER_clamp]
|Voltage   I(typ)   I(min)   I(max)
-1.085V   71.41mA    95.35mA    58.18mA
-1.062V   59.23mA    82.55mA    46.99mA
-1.039V   48.36mA    70.56mA    37.71mA
-1.016V   38.97mA    59.53mA    30.53mA
-970mV    25.17mA    40.76mA    21.88mA
-924mV    17.37mA    26.93mA    17.87mA
-901mV    15.03mA    21.86mA    16.59mA
-855mV    12.01mA    14.79mA    14.5mA
-763mV    8.448mA    8.108mA    10.89mA
-533mV    2.369mA    2.267mA    3.272mA
-349mV    143.9uA    291.4uA    171.3uA
1.1V      0A         0A         0A
[Ramp]
| variable   typ   min   max
dV/dt_r   0.345/0.167n   0.329/0.213n   0.354/0.135n
dV/dt_f   0.349/0.119n   0.341/0.162n   0.349/96.877p
R_load = 50.000
[Rising Waveform]
R_fixture = 50.000
V_fixture = 0.000
V_fixture_min = 0.000
V_fixture_max = 0.000
|  time   V(typ)   V(min)   V(max)
0s        2.075uV    7.548uV    855.7nV
397ps     -248.2uV   75.08uV    7.503mV
439ps     -1.352mV   68.19uV    71.82mV
516ps     8.211mV    -1.202mV   320.1mV
658ps     314.7mV    40.06mV    562.5mV
744ps     473.3mV    194.9mV    596.6mV
856ps     558.2mV    393.3mV    610.3mV
1.063ns   593mV      533.8mV    615.7mV
1.487ns   600.5mV    570mV      616.9mV
10ns      601.2mV    574.3mV    617mV
[Rising Waveform]
R_fixture = 50.000
V_fixture = 0.550
V_fixture_min = 0.534
V_fixture_max = 0.568
|  time   V(typ)   V(min)   V(max)
0s        258.9mV    249.5mV    275.5mV
402ps     258.6mV    249.6mV    282.2mV
428ps     258.3mV    249.5mV    327.1mV
515ps     270.7mV    248.9mV    653.2mV
638ps     596.1mV    283.6mV    837.1mV
713ps     744.1mV    443mV      861.5mV
796ps     811.4mV    624.9mV    870.6mV
966ps     844.6mV    781mV      875.2mV
1.286ns   851.7mV    818.5mV    876.3mV
10ns      852.5mV    823.8mV    876.4mV
[Falling Waveform]
R_fixture = 50.000
V_fixture = 0.550
V_fixture_min = 0.534
V_fixture_max = 0.568
|  time   V(typ)   V(min)   V(max)
0s        852.5mV    823.8mV    876.4mV
384ps     853.2mV    823.9mV    875.7mV
414ps     854.6mV    824.1mV    813mV
489ps     848.3mV    826.1mV    483mV
530ps     773.4mV    826.6mV    378.3mV
616ps     453.7mV    787.2mV    301.3mV
736ps     292.1mV    475.8mV    280.4mV
869ps     265.8mV    295.3mV    276.6mV
1.169ns   259.6mV    253.8mV    275.6mV
10ns      258.9mV    249.5mV    275.5mV
[Falling Waveform]
R_fixture = 50.000
V_fixture = 0.000
V_fixture_min = 0.000
V_fixture_max = 0.000
|  time   V(typ)   V(min)   V(max)
0s        601.2mV    574.3mV    617mV
384ps     602.6mV    574.5mV    613.2mV
411ps     604.2mV    574.9mV    548.9mV
484ps     594.4mV    577.8mV    213.4mV
522ps     514.4mV    578.2mV    108.3mV
603ps     191mV      534.5mV    27.66mV
729ps     24.55mV    172.6mV    4.245mV
839ps     5.372mV    33.66mV    1.071mV
1.069ns   552.3uV    2.346mV    137.3uV
10ns      2.075uV    7.548uV    855.7nV
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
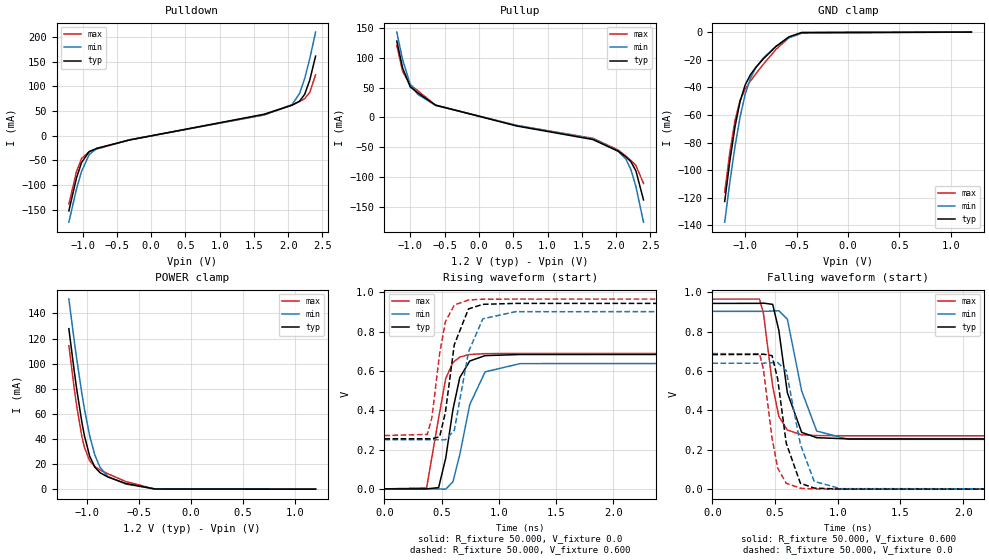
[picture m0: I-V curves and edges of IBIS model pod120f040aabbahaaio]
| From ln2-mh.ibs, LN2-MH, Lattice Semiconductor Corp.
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|   Model pod120f040aabbahaaio
[Model] pod120f040aabbahaaio
| Clamp models do not include dynamic input termination. Please refer to
| the pod120axxxaabbahaain model for input termination.
Model_type I/O
Polarity   Non-Inverting
Enable   Active-Low
Vinl =  0.800V
Vinh =  1.000V
Vmeas =  0.600V
Cref =  20.000pF
Rref =  50.000
Vref =  0.600V
C_comp   2.000pF   1.500pF   2.500pF
[Temperature Range]   25.000   0.125k   -40.000
[Voltage Range]   1.200V   1.160V   1.240V
[C Comp Corner]
C_comp   2.000pF   1.500pF   2.500pF
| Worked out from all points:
|   slope of the pulldown table from 0 to 0.18 V, typ, clamps not added: 36.9 ohm
|   slope of the pullup table from 0 to 0.18 V, typ, clamps not added: 37.3 ohm
|   GND clamp passes 1 mA (typ) near -0.50 V on its own axis
|   POWER clamp passes 1 mA (typ) near -0.45 V on its own axis
|   rising waveform, R_fixture 50.000, V_fixture 0.0: 20-80 % time 118ps typ, 146ps min, 109ps max; typ from 0 V to 0.684 V
|   rising waveform, R_fixture 50.000, V_fixture 0.600: 20-80 % time 102ps typ, 124ps min, 96.4ps max; typ from 0.255 V to 0.943 V
|   falling waveform, R_fixture 50.000, V_fixture 0.600: 20-80 % time 98.5ps typ, 126ps min, 90.9ps max; typ from 0.943 V to 0.255 V
|   falling waveform, R_fixture 50.000, V_fixture 0.0: 20-80 % time 95.1ps typ, 119ps min, 89.2ps max; typ from 0.684 V to 0 V
[Pulldown]
|Voltage   I(typ)   I(min)   I(max)
-1.2V     -152.4mA   -175.4mA   -138.5mA
-1.089V   -85.71mA   -108.2mA   -73.08mA
-1.015V   -54.37mA   -72.38mA   -46.19mA
-904mV    -32.27mA   -38.45mA   -32.39mA
-793mV    -25.71mA   -25.48mA   -26.97mA
-312mV    -8.528mA   -8.488mA   -8.073mA
1.649V    43.64mA    42.58mA    42.18mA
2.056V    61.9mA     63mA       62.51mA
2.167V    70.28mA    86.13mA    69.41mA
2.241V    84.04mA    116.1mA    75.18mA
2.315V    112.8mA    156.3mA    87.92mA
2.4V      161.6mA    210.3mA    123.8mA
[Pullup]
|Voltage   I(typ)   I(min)   I(max)
-1.2V     128mA      143mA      120.9mA
-1.115V   82.63mA    96.63mA    77.06mA
-1.004V   51.07mA    55.48mA    54.65mA
-893mV    41.03mA    38.53mA    44.59mA
-634mV    20.49mA    20.01mA    20.44mA
550mV     -14.53mA   -13.49mA   -13.74mA
1.66V     -37.19mA   -35.96mA   -35.08mA
2.03V     -56.8mA    -56.78mA   -54.77mA
2.141V    -66.06mA   -69.74mA   -64.94mA
2.215V    -74.23mA   -87.19mA   -72.14mA
2.289V    -89.63mA   -115.9mA   -80.62mA
2.4V      -138.5mA   -175.9mA   -110.9mA
[GND_clamp]
|Voltage   I(typ)   I(min)   I(max)
-1.2V     -122.7mA   -137.7mA   -116mA
-1.15V    -93.48mA   -108.7mA   -87.06mA
-1.1V     -68.68mA   -82.93mA   -64.19mA
-1.05V    -50.06mA   -61.34mA   -49.53mA
-1V       -38.15mA   -44.88mA   -41.24mA
-950mV    -30.92mA   -33.54mA   -35.51mA
-900mV    -25.81mA   -26.1mA    -30.49mA
-825mV    -19.48mA   -18.8mA    -23.39mA
-700mV    -10.29mA   -10.29mA   -12.48mA
-575mV    -3.418mA   -4.142mA   -4.045mA
-450mV    -323.4uA   -814.3uA   -268.3uA
1.2V      0A         0A         0A
[POWER_clamp]
|Voltage   I(typ)   I(min)   I(max)
-1.175V   127.9mA    151.5mA    114.3mA
-1.125V   95.1mA     119.3mA    81.28mA
-1.1V     80mA       104.2mA    66.46mA
-1.05V    53.45mA    76.25mA    42.06mA
-1.025V   42.52mA    63.79mA    33.25mA
-975mV    26.42mA    42.64mA    22.65mA
-925mV    17.53mA    27.24mA    17.97mA
-875mV    13.15mA    17.46mA    15.37mA
-800mV    9.709mA    10.06mA    12.3mA
-625mV    4.479mA    4.015mA    6.021mA
-350mV    147.7uA    296.5uA    176.7uA
1.2V      0A         0A         0A
[Ramp]
| variable   typ   min   max
dV/dt_r   0.410/0.118n   0.384/0.146n   0.413/0.109n
dV/dt_f   0.414/0.106n   0.397/0.140n   0.418/93.486p
R_load = 50.000
[Rising Waveform]
R_fixture= 50.000
V_fixture= 0.0
V_fixture_min= 0.0
V_fixture_max= 0.0
|time   V(typ)   V(min)   V(max)
0s        1.143uV    6.223uV    521.7nV
368ps     63.62uV    46.69uV    4.902mV
473ps     6.489mV    -305.6uV   359.5mV
535ps     155.9mV    -1.474mV   561.1mV
598ps     402.9mV    35.89mV    642.5mV
658ps     566.1mV    174.1mV    670.3mV
745ps     650.2mV    428.5mV    683.4mV
879ps     677.6mV    595mV      687.7mV
1.185ns   683.3mV    637mV      688.6mV
10ns      683.6mV    639.6mV    688.7mV
[Rising Waveform]
R_fixture= 50.000
V_fixture= 0.600
V_fixture_min= 0.583
V_fixture_max= 0.619
|time   V(typ)   V(min)   V(max)
0s        254.7mV    249.8mV    271mV
374ps     254.8mV    249.9mV    276.9mV
415ps     254.3mV    249.9mV    364mV
482ps     265.2mV    249.5mV    688.6mV
532ps     387.9mV    249.6mV    849.9mV
610ps     733.5mV    297.4mV    935mV
734ps     915.1mV    696.6mV    960.7mV
859ps     938.4mV    864.6mV    964.3mV
1.144ns   943.2mV    901mV      965.1mV
10ns      943.4mV    903.1mV    965.2mV
[Falling Waveform]
R_fixture= 50.000
V_fixture= 0.600
V_fixture_min= 0.583
V_fixture_max= 0.619
|time   V(typ)   V(min)   V(max)
0s        943.4mV    903.1mV    965.1mV
376ps     943.7mV    903.1mV    965.5mV
407ps     944.9mV    903.2mV    893.9mV
481ps     938.6mV    904.7mV    522.4mV
530ps     807mV      906.3mV    369.5mV
598ps     490mV      863.2mV    300.5mV
712ps     288.6mV    499.5mV    276.2mV
832ps     261.4mV    295.1mV    272.2mV
1.082ns   255.4mV    253.4mV    271.1mV
10ns      254.7mV    249.8mV    271mV
[Falling Waveform]
R_fixture= 50.000
V_fixture= 0.0
V_fixture_min= 0.0
V_fixture_max= 0.0
|time   V(typ)   V(min)   V(max)
0s        683.6mV    639.6mV    688.7mV
376ps     684.2mV    639.7mV    686.9mV
407ps     685.7mV    639.9mV    608.7mV
476ps     678mV      641.7mV    258.8mV
521ps     559mV      642.8mV    106.6mV
589ps     233.7mV    601.8mV    29.96mV
702ps     29.87mV    227.3mV    4.782mV
812ps     5.559mV    39.65mV    1.087mV
1.022ns   549.5uV    2.477mV    144.4uV
10ns      1.158uV    6.231uV    540nV
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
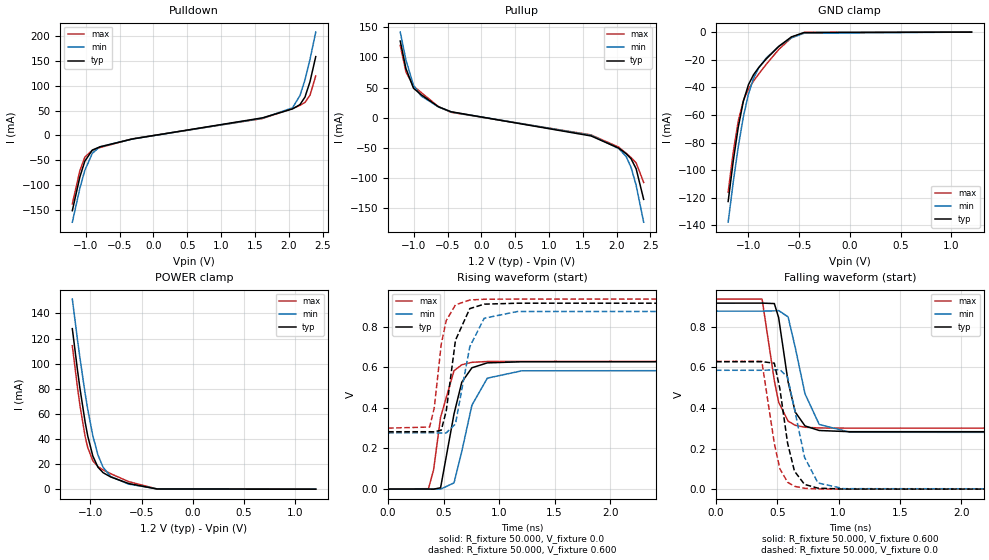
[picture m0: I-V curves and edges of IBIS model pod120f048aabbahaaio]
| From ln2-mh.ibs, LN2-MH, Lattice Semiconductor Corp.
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|   Model pod120f048aabbahaaio
[Model] pod120f048aabbahaaio
| Clamp models do not include dynamic input termination. Please refer to
| the pod120axxxaabbahaain model for input termination.
Model_type I/O
Polarity   Non-Inverting
Enable   Active-Low
Vinl =  0.800V
Vinh =  1.000V
Vmeas =  0.600V
Cref =  20.000pF
Rref =  50.000
Vref =  0.600V
C_comp   2.000pF   1.500pF   2.500pF
[Temperature Range]   25.000   0.125k   -40.000
[Voltage Range]   1.200V   1.160V   1.240V
[C Comp Corner]
C_comp   2.000pF   1.500pF   2.500pF
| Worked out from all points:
|   slope of the pulldown table from 0 to 0.18 V, typ, clamps not added: 44.5 ohm
|   slope of the pullup table from 0 to 0.18 V, typ, clamps not added: 44.9 ohm
|   GND clamp passes 1 mA (typ) near -0.50 V on its own axis
|   POWER clamp passes 1 mA (typ) near -0.45 V on its own axis
|   rising waveform, R_fixture 50.000, V_fixture 0.0: 20-80 % time 121ps typ, 153ps min, 108ps max; typ from 0 V to 0.627 V
|   rising waveform, R_fixture 50.000, V_fixture 0.600: 20-80 % time 101ps typ, 127ps min, 90.8ps max; typ from 0.282 V to 0.916 V
|   falling waveform, R_fixture 50.000, V_fixture 0.600: 20-80 % time 105ps typ, 136ps min, 94.6ps max; typ from 0.916 V to 0.282 V
|   falling waveform, R_fixture 50.000, V_fixture 0.0: 20-80 % time 101ps typ, 126ps min, 93.5ps max; typ from 0.627 V to 0 V
[Pulldown]
|Voltage   I(typ)   I(min)   I(max)
-1.2V     -150.9mA   -174mA     -137.1mA
-1.089V   -83.5mA    -106.2mA   -70.74mA
-1.015V   -51.59mA   -69.99mA   -43.42mA
-904mV    -29.33mA   -35.67mA   -29.64mA
-793mV    -22.9mA    -22.74mA   -24.33mA
-312mV    -7.083mA   -7.066mA   -6.683mA
1.612V    35.31mA    34.52mA    34mA
2.056V    53.27mA    55.43mA    53.91mA
2.167V    61.89mA    80.22mA    60.44mA
2.241V    77.15mA    111.6mA    66.35mA
2.315V    107.9mA    152.7mA    80.79mA
2.4V      158.2mA    207.4mA    119.5mA
[Pullup]
|Voltage   I(typ)   I(min)   I(max)
-1.2V     127.1mA    142mA      120mA
-1.115V   81.3mA     95.43mA    75.78mA
-1.004V   48.86mA    53.76mA    52.31mA
-893mV    38.28mA    36.21mA    42.01mA
-634mV    18.06mA    17.76mA    18.21mA
-449mV    9.831mA    9.596mA    8.994mA
1.623V    -30.34mA   -29.2mA    -28.61mA
2.03V     -50.48mA   -50.95mA   -48.79mA
2.141V    -59.83mA   -64.48mA   -59mA
2.215V    -68.36mA   -82.83mA   -66.26mA
2.289V    -84.85mA   -112.4mA   -75.03mA
2.4V      -135.5mA   -173.4mA   -107.4mA
[GND_clamp]
|Voltage   I(typ)   I(min)   I(max)
-1.2V     -122.7mA   -137.7mA   -116mA
-1.15V    -93.48mA   -108.7mA   -87.06mA
-1.1V     -68.68mA   -82.93mA   -64.19mA
-1.05V    -50.06mA   -61.34mA   -49.53mA
-1V       -38.15mA   -44.88mA   -41.24mA
-950mV    -30.91mA   -33.54mA   -35.51mA
-900mV    -25.81mA   -26.1mA    -30.49mA
-825mV    -19.48mA   -18.8mA    -23.39mA
-700mV    -10.29mA   -10.29mA   -12.48mA
-575mV    -3.418mA   -4.142mA   -4.045mA
-450mV    -323.4uA   -814.3uA   -268.3uA
1.2V      0A         0A         0A
[POWER_clamp]
|Voltage   I(typ)   I(min)   I(max)
-1.175V   127.9mA    151.5mA    114.3mA
-1.125V   95.1mA     119.3mA    81.28mA
-1.1V     80mA       104.2mA    66.46mA
-1.05V    53.45mA    76.25mA    42.06mA
-1.025V   42.52mA    63.79mA    33.25mA
-975mV    26.42mA    42.64mA    22.65mA
-925mV    17.53mA    27.24mA    17.97mA
-875mV    13.15mA    17.46mA    15.37mA
-800mV    9.709mA    10.06mA    12.3mA
-625mV    4.479mA    4.015mA    6.021mA
-350mV    147.7uA    296.5uA    176.7uA
1.2V      0A         0A         0A
[Ramp]
| variable   typ   min   max
dV/dt_r   0.376/0.121n   0.351/0.153n   0.378/0.108n
dV/dt_f   0.380/0.113n   0.365/0.152n   0.383/95.779p
R_load = 50.000
[Rising Waveform]
R_fixture= 50.000
V_fixture= 0.0
V_fixture_min= 0.0
V_fixture_max= 0.0
|time   V(typ)   V(min)   V(max)
0s        1.292uV    7.005uV    589.2nV
364ps     77.03uV    53.51uV    1.916mV
410ps     -440.8uV   74.49uV    94.81mV
473ps     6.476mV    -295.8uV   353.5mV
594ps     370.2mV    30.46mV    583mV
664ps     526.3mV    185.3mV    612.3mV
755ps     597.4mV    412.8mV    624.4mV
894ps     621.7mV    546.4mV    628.4mV
1.206ns   627.1mV    582.8mV    629.3mV
10ns      627.3mV    585.3mV    629.4mV
[Rising Waveform]
R_fixture= 50.000
V_fixture= 0.600
V_fixture_min= 0.583
V_fixture_max= 0.619
|time   V(typ)   V(min)   V(max)
0s        282.5mV    276.8mV    300.3mV
374ps     282.5mV    276.9mV    305.6mV
416ps     282.1mV    276.9mV    399.7mV
479ps     290.2mV    276.5mV    713.8mV
524ps     384.6mV    276.7mV    830.1mV
607ps     733mV      320.8mV    907.4mV
736ps     889mV      701.1mV    931.5mV
866ps     910.9mV    841.6mV    935.1mV
1.166ns   915.6mV    874.7mV    935.9mV
10ns      915.9mV    876.6mV    936mV
[Falling Waveform]
R_fixture= 50.000
V_fixture= 0.600
V_fixture_min= 0.583
V_fixture_max= 0.619
|time   V(typ)   V(min)   V(max)
0s        915.9mV    876.6mV    936mV
376ps     916.1mV    876.6mV    936mV
476ps     913.9mV    877.9mV    534.4mV
511ps     844.8mV    879.5mV    428.2mV
588ps     528.5mV    848.2mV    335.2mV
647ps     379.2mV    696.2mV    314.2mV
726ps     311.4mV    469.7mV    304.8mV
842ps     288.8mV    318.5mV    301.3mV
1.092ns   283mV      280.3mV    300.4mV
10ns      282.5mV    276.8mV    300.3mV
[Falling Waveform]
R_fixture= 50.000
V_fixture= 0.0
V_fixture_min= 0.0
V_fixture_max= 0.0
|time   V(typ)   V(min)   V(max)
0s        627.3mV    585.3mV    629.4mV
374ps     627.9mV    585.3mV    628.8mV
476ps     620.3mV    587.4mV    224.5mV
521ps     494.5mV    588.3mV    100.2mV
584ps     226.6mV    551.7mV    34.16mV
640ps     88.86mV    394.5mV    14.01mV
722ps     23.43mV    157.4mV    4.199mV
832ps     4.968mV    30.52mV    1.01mV
1.041ns   514.2uV    2.33mV     131.1uV
10ns      1.308uV    7.016uV    608nV
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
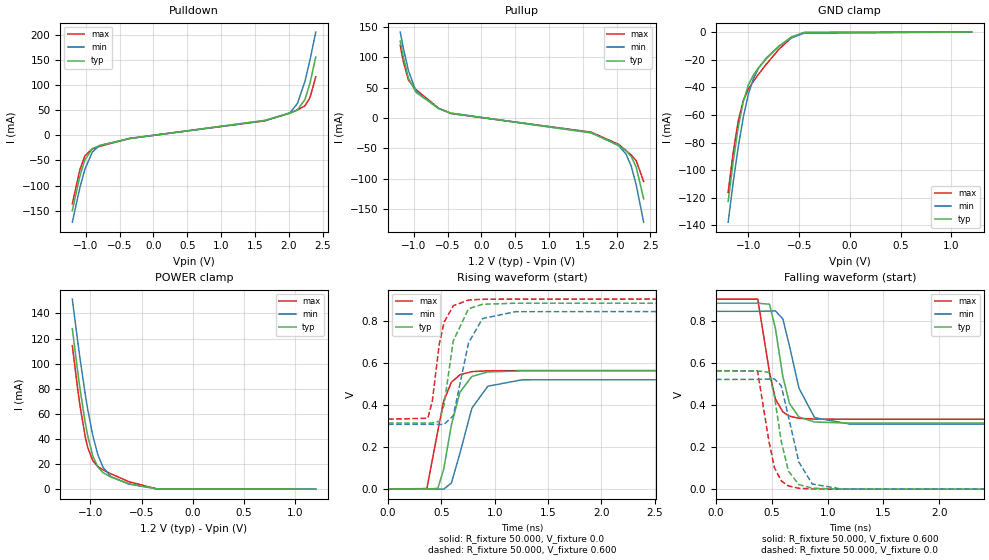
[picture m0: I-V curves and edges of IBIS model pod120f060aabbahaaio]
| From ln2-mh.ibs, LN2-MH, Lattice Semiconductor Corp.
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|   Model pod120f060aabbahaaio
[Model] pod120f060aabbahaaio
| Clamp models do not include dynamic input termination. Please refer to
| the pod120axxxaabbahaain model for input termination.
Model_type I/O
Polarity   Non-Inverting
Enable   Active-Low
Vinl =  0.800V
Vinh =  1.000V
Vmeas =  0.600V
Cref =  20.000pF
Rref =  50.000
Vref =  0.600V
C_comp   2.000pF   1.500pF   2.500pF
[Temperature Range]   25.000   0.125k   -40.000
[Voltage Range]   1.200V   1.160V   1.240V
[C Comp Corner]
C_comp   2.000pF   1.500pF   2.500pF
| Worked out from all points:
|   slope of the pulldown table from 0 to 0.18 V, typ, clamps not added: 54.8 ohm
|   slope of the pullup table from 0 to 0.18 V, typ, clamps not added: 55.5 ohm
|   GND clamp passes 1 mA (typ) near -0.50 V on its own axis
|   POWER clamp passes 1 mA (typ) near -0.45 V on its own axis
|   rising waveform, R_fixture 50.000, V_fixture 0.0: 20-80 % time 137ps typ, 172ps min, 122ps max; typ from 0 V to 0.562 V
|   rising waveform, R_fixture 50.000, V_fixture 0.600: 20-80 % time 111ps typ, 140ps min, 101ps max; typ from 0.314 V to 0.884 V
|   falling waveform, R_fixture 50.000, V_fixture 0.600: 20-80 % time 114ps typ, 147ps min, 103ps max; typ from 0.884 V to 0.314 V
|   falling waveform, R_fixture 50.000, V_fixture 0.0: 20-80 % time 110ps typ, 137ps min, 103ps max; typ from 0.562 V to 0 V
[Pulldown]
|Voltage   I(typ)   I(min)   I(max)
-1.2V     -149.6mA   -172.7mA   -136mA
-1.089V   -81.51mA   -104.5mA   -68.7mA
-1.015V   -49.07mA   -67.83mA   -40.98mA
-904mV    -26.65mA   -33.13mA   -27.21mA
-793mV    -20.32mA   -20.23mA   -22.01mA
-349mV    -6.516mA   -6.544mA   -6.202mA
1.649V    29.6mA     29.08mA    28.54mA
2.019V    43.56mA    44.45mA    44.25mA
2.13V     50.29mA    63.23mA    50.23mA
2.241V    71.16mA    107.5mA    58.54mA
2.315V    103.7mA    149.5mA    74.75mA
2.4V      155.2mA    204.8mA    116mA
[Pullup]
|Voltage   I(typ)   I(min)   I(max)
-1.2V     126.2mA    141.1mA    119.3mA
-1.152V   98.36mA    113.4mA    91.68mA
-1.078V   65.05mA    77.45mA    62.24mA
-967mV    42.18mA    43.93mA    46.72mA
-634mV    15.79mA    15.62mA    16.18mA
-449mV    8.001mA    7.891mA    7.334mA
1.623V    -24.49mA   -23.7mA    -23.12mA
2.03V     -44.47mA   -45.37mA   -43.22mA
2.141V    -53.9mA    -59.47mA   -53.46mA
2.215V    -62.82mA   -78.71mA   -60.77mA
2.289V    -80.43mA   -109.2mA   -69.86mA
2.4V      -132.7mA   -171mA     -104.2mA
[GND_clamp]
|Voltage   I(typ)   I(min)   I(max)
-1.2V     -122.7mA   -137.7mA   -116mA
-1.15V    -93.48mA   -108.7mA   -87.06mA
-1.1V     -68.68mA   -82.93mA   -64.19mA
-1.05V    -50.06mA   -61.34mA   -49.53mA
-1V       -38.15mA   -44.88mA   -41.24mA
-950mV    -30.91mA   -33.54mA   -35.51mA
-900mV    -25.81mA   -26.1mA    -30.49mA
-825mV    -19.48mA   -18.8mA    -23.39mA
-700mV    -10.29mA   -10.29mA   -12.48mA
-575mV    -3.418mA   -4.142mA   -4.045mA
-450mV    -323.4uA   -814.3uA   -268.3uA
1.2V      0A         0A         0A
[POWER_clamp]
|Voltage   I(typ)   I(min)   I(max)
-1.175V   127.9mA    151.5mA    114.3mA
-1.125V   95.1mA     119.3mA    81.28mA
-1.1V     80mA       104.2mA    66.46mA
-1.05V    53.45mA    76.25mA    42.06mA
-1.025V   42.52mA    63.79mA    33.25mA
-975mV    26.42mA    42.64mA    22.65mA
-925mV    17.53mA    27.24mA    17.97mA
-875mV    13.15mA    17.46mA    15.37mA
-800mV    9.709mA    10.06mA    12.3mA
-625mV    4.479mA    4.015mA    6.021mA
-350mV    147.7uA    296.5uA    176.7uA
1.2V      0A         0A         0A
[Ramp]
| variable   typ   min   max
dV/dt_r   0.337/0.137n   0.313/0.172n   0.338/0.122n
dV/dt_f   0.343/0.125n   0.328/0.169n   0.344/0.105n
R_load = 50.000
[Rising Waveform]
R_fixture= 50.000
V_fixture= 0.0
V_fixture_min= 0.0
V_fixture_max= 0.0
|time   V(typ)   V(min)   V(max)
0s        1.465uV    7.91uV     665.2nV
364ps     77.11uV    62.65uV    2.06mV
467ps     3.06mV     -191.2uV   277.1mV
522ps     94.84mV    -682uV     419.2mV
594ps     304.3mV    28.67mV    507.7mV
674ps     460.3mV    169.4mV    543.6mV
786ps     535.3mV    384.4mV    558.4mV
936ps     556.9mV    489mV      562.4mV
1.256ns   561.8mV    519.4mV    563.2mV
10ns      562.1mV    521.7mV    563.3mV
[Rising Waveform]
R_fixture= 50.000
V_fixture= 0.600
V_fixture_min= 0.583
V_fixture_max= 0.619
|time   V(typ)   V(min)   V(max)
0s        314mV      307.6mV    332.3mV
373ps     314mV      307.6mV    336.7mV
415ps     313.7mV    307.6mV    418.8mV
481ps     322.9mV    307.3mV    692.1mV
526ps     402.7mV    307.6mV    794.2mV
612ps     705.1mV    348.8mV    871.8mV
755ps     857.6mV    695mV      898.8mV
886ps     878.6mV    810.7mV    902.5mV
1.195ns   883.7mV    843.5mV    903.4mV
10ns      883.9mV    845.6mV    903.5mV
[Falling Waveform]
R_fixture= 50.000
V_fixture= 0.600
V_fixture_min= 0.583
V_fixture_max= 0.619
|time   V(typ)   V(min)   V(max)
0s        883.9mV    845.6mV    903.5mV
374ps     884.1mV    845.6mV    903.9mV
479ps     879.5mV    846.9mV    555.5mV
532ps     765mV      847.9mV    428.9mV
599ps     534.4mV    809.1mV    367.3mV
659ps     406.6mV    679.1mV    347.1mV
743ps     343.1mV    480.3mV    337.1mV
883ps     319.3mV    340.1mV    333.2mV
1.199ns   314.3mV    309.6mV    332.3mV
10ns      314mV      307.6mV    332.3mV
[Falling Waveform]
R_fixture= 50.000
V_fixture= 0.0
V_fixture_min= 0.0
V_fixture_max= 0.0
|time   V(typ)   V(min)   V(max)
0s        562mV      521.7mV    563.2mV
372ps     562.6mV    521.7mV    562.7mV
474ps     555.7mV    523.6mV    227.7mV
523ps     443.6mV    524mV      103.3mV
584ps     228.6mV    492.2mV    39.82mV
649ps     85.44mV    344.7mV    15.32mV
742ps     21.83mV    128.8mV    4.262mV
862ps     4.572mV    24.75mV    970.8uV
1.113ns   360.4uV    1.562mV    94.16uV
10ns      1.483uV    7.926uV    686.8nV
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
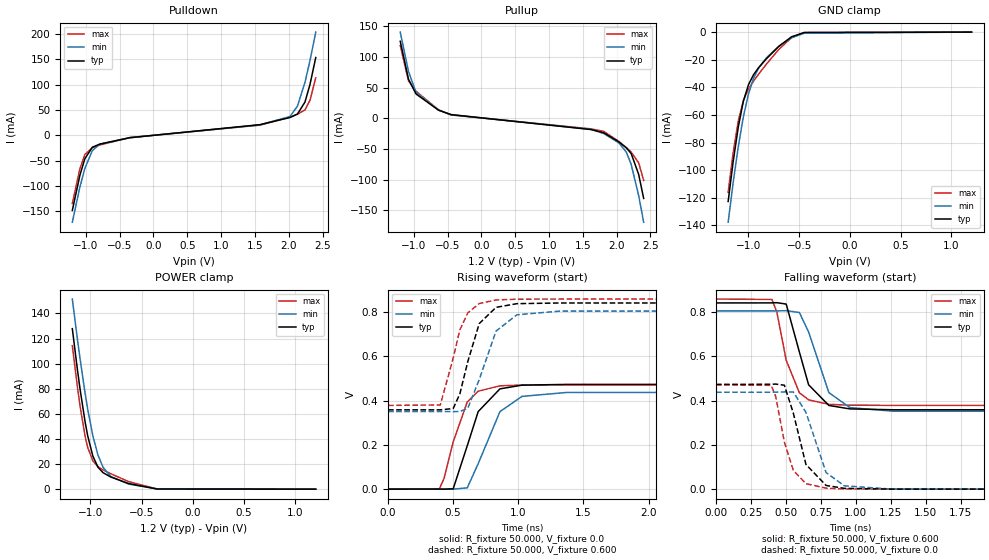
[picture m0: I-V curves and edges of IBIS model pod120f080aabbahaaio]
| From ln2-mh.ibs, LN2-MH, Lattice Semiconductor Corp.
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|   Model pod120f080aabbahaaio
[Model] pod120f080aabbahaaio
| Clamp models do not include dynamic input termination. Please refer to
| the pod120axxxaabbahaain model for input termination.
Model_type I/O
Polarity   Non-Inverting
Enable   Active-Low
Vinl =  0.800V
Vinh =  1.000V
Vmeas =  0.600V
Cref =  20.000pF
Rref =  50.000
Vref =  0.600V
C_comp   2.000pF   1.500pF   2.500pF
[Temperature Range]   25.000   0.125k   -40.000
[Voltage Range]   1.200V   1.160V   1.240V
[C Comp Corner]
C_comp   2.000pF   1.500pF   2.500pF
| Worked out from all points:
|   slope of the pulldown table from 0 to 0.18 V, typ, clamps not added: 73.8 ohm
|   slope of the pullup table from 0 to 0.18 V, typ, clamps not added: 74.4 ohm
|   GND clamp passes 1 mA (typ) near -0.50 V on its own axis
|   POWER clamp passes 1 mA (typ) near -0.45 V on its own axis
|   rising waveform, R_fixture 50.000, V_fixture 0.0: 20-80 % time 155ps typ, 184ps min, 141ps max; typ from 0 V to 0.473 V
|   rising waveform, R_fixture 50.000, V_fixture 0.600: 20-80 % time 135ps typ, 158ps min, 122ps max; typ from 0.358 V to 0.84 V
|   falling waveform, R_fixture 50.000, V_fixture 0.600: 20-80 % time 119ps typ, 142ps min, 109ps max; typ from 0.84 V to 0.358 V
|   falling waveform, R_fixture 50.000, V_fixture 0.0: 20-80 % time 114ps typ, 134ps min, 105ps max; typ from 0.473 V to 0 V
[Pulldown]
|Voltage   I(typ)   I(min)   I(max)
-1.2V     -148.6mA   -171.8mA   -134.9mA
-1.089V   -79.59mA   -102.9mA   -66.56mA
-1.015V   -46.45mA   -65.69mA   -38.29mA
-904mV    -23.77mA   -30.44mA   -24.5mA
-793mV    -17.54mA   -17.53mA   -19.41mA
-349mV    -4.882mA   -4.944mA   -4.63mA
1.575V    20.81mA    20.49mA    19.96mA
2.019V    35.02mA    36.94mA    35.75mA
2.13V     41.9mA     57.64mA    41.37mA
2.241V    65.57mA    104.5mA    50.12mA
2.315V    100.4mA    147.6mA    69.01mA
2.4V      153.4mA    203.7mA    113.3mA
[Pullup]
|Voltage   I(typ)   I(min)   I(max)
-1.2V     125.7mA    140.7mA    118.8mA
-1.078V   63.89mA    76.59mA    60.93mA
-967mV    39.84mA    42.28mA    44.24mA
-634mV    13.36mA    13.37mA    13.95mA
-449mV    6.044mA    6.101mA    5.5mA
1.623V    -18.3mA    -17.97mA   -17.18mA
1.808V    -23.44mA   -24.75mA   -21.19mA
2.03V     -38.25mA   -39.69mA   -37.34mA
2.141V    -47.82mA   -54.61mA   -47.63mA
2.215V    -57.29mA   -75mA      -55.01mA
2.326V    -91.36mA   -125.9mA   -72.48mA
2.4V      -130.6mA   -169.4mA   -101.3mA
[GND_clamp]
|Voltage   I(typ)   I(min)   I(max)
-1.2V     -122.7mA   -137.7mA   -116mA
-1.15V    -93.48mA   -108.7mA   -87.06mA
-1.1V     -68.68mA   -82.93mA   -64.19mA
-1.05V    -50.06mA   -61.34mA   -49.53mA
-1V       -38.15mA   -44.88mA   -41.24mA
-950mV    -30.91mA   -33.54mA   -35.51mA
-900mV    -25.81mA   -26.1mA    -30.49mA
-825mV    -19.48mA   -18.8mA    -23.39mA
-700mV    -10.29mA   -10.29mA   -12.48mA
-575mV    -3.418mA   -4.142mA   -4.045mA
-450mV    -323.4uA   -814.3uA   -268.3uA
1.2V      0A         0A         0A
[POWER_clamp]
|Voltage   I(typ)   I(min)   I(max)
-1.175V   127.9mA    151.5mA    114.3mA
-1.125V   95.1mA     119.3mA    81.28mA
-1.1V     80mA       104.2mA    66.46mA
-1.05V    53.45mA    76.25mA    42.06mA
-1.025V   42.52mA    63.79mA    33.25mA
-975mV    26.42mA    42.64mA    22.65mA
-925mV    17.53mA    27.24mA    17.97mA
-875mV    13.15mA    17.46mA    15.37mA
-800mV    9.709mA    10.06mA    12.3mA
-625mV    4.479mA    4.015mA    6.021mA
-350mV    147.7uA    296.5uA    176.7uA
1.2V      0A         0A         0A
[Ramp]
| variable   typ   min   max
dV/dt_r   0.284/0.155n   0.263/0.184n   0.282/0.141n
dV/dt_f   0.290/0.134n   0.277/0.164n   0.289/0.120n
R_load = 50.000
[Rising Waveform]
R_fixture= 50.000
V_fixture= 0.0
V_fixture_min= 0.0
V_fixture_max= 0.0
|time   V(typ)   V(min)   V(max)
0s        1.7uV      9.144uV    771nV
393ps     190.4uV    115.8uV    64.65uV
431ps     -250.6uV   215.1uV    49.76mV
500ps     1.622mV    -219.3uV   213.2mV
608ps     195.7mV    5.888mV    393.5mV
692ps     350mV      114.8mV    442mV
859ps     452.6mV    349.8mV    466.4mV
1.028ns   469.4mV    418.6mV    469.8mV
1.372ns   472.7mV    436.4mV    470.5mV
10ns      472.9mV    437.5mV    470.5mV
[Rising Waveform]
R_fixture= 50.000
V_fixture= 0.600
V_fixture_min= 0.583
V_fixture_max= 0.619
|time   V(typ)   V(min)   V(max)
0s        357.8mV    350mV      378mV
401ps     357.9mV    350.1mV    379.7mV
500ps     363.7mV    349.8mV    591.1mV
551ps     429.6mV    350.3mV    718.8mV
612ps     575.4mV    364.8mV    795.3mV
700ps     747.3mV    494.8mV    837.7mV
829ps     820.6mV    713.5mV    853.9mV
989ps     837.2mV    786.9mV    857.4mV
1.318ns   840.3mV    803.6mV    858mV
10ns      840.5mV    804.5mV    858mV
[Falling Waveform]
R_fixture= 50.000
V_fixture= 0.600
V_fixture_min= 0.583
V_fixture_max= 0.619
|time   V(typ)   V(min)   V(max)
0s        840.5mV    804.5mV    858mV
400ps     840.7mV    804.6mV    856.3mV
435ps     841.7mV    804.6mV    799.3mV
502ps     835.3mV    805.6mV    581.6mV
596ps     619.2mV    797.4mV    435.3mV
662ps     471.1mV    709.4mV    403mV
807ps     377.8mV    435.8mV    382.8mV
957ps     362.3mV    368.2mV    379.1mV
1.267ns   358.3mV    351.9mV    378.1mV
10ns      357.8mV    350mV      378mV
[Falling Waveform]
R_fixture= 50.000
V_fixture= 0.0
V_fixture_min= 0.0
V_fixture_max= 0.0
|time   V(typ)   V(min)   V(max)
0s        472.9mV    437.5mV    470.5mV
395ps     473.4mV    437.6mV    468.7mV
427ps     474.3mV    437.7mV    417.7mV
489ps     469.1mV    438.9mV    212.2mV
553ps     342.8mV    438.4mV    84.51mV
643ps     111.5mV    346.5mV    24.97mV
787ps     16.72mV    74.93mV    4.232mV
917ps     3.74mV     15.08mV    1.067mV
1.247ns   270uV      748.1uV    100.1uV
10ns      1.716uV    9.154uV    790.9nV
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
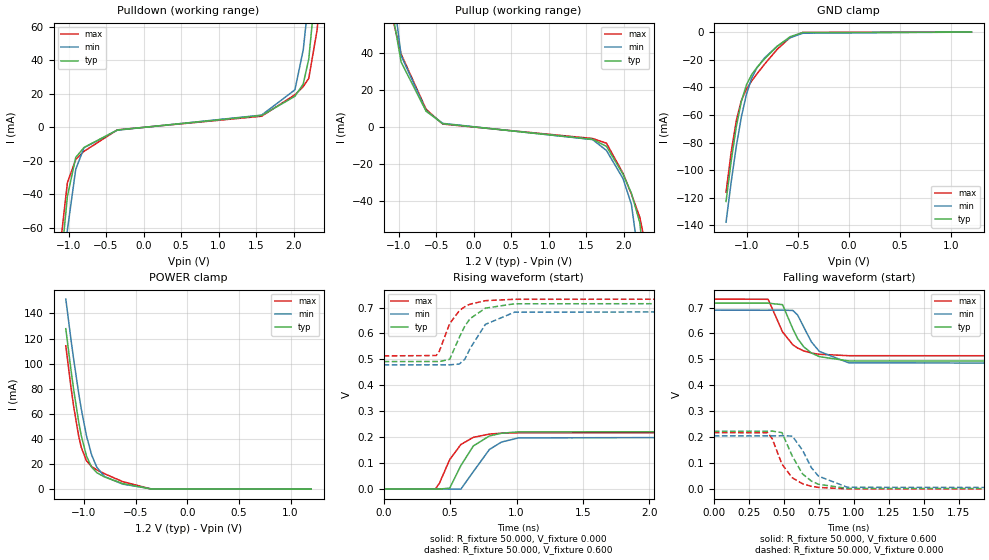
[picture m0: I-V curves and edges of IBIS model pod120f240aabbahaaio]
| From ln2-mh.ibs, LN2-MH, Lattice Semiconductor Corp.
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|   Model pod120f240aabbahaaio
[Model] pod120f240aabbahaaio
| Clamp models do not include dynamic input termination. Please refer to
| the pod120axxxaabbahaain model for input termination.
Model_type I/O
Polarity   Non-Inverting
Enable   Active-Low
Vinl =  0.800V
Vinh =  1.000V
Vmeas =  0.600V
Cref =  20.000pF
Rref =  50.000
Vref =  0.600V
C_comp   2.000pF   1.500pF   2.500pF
[Temperature Range]   25.000   0.125k   -40.000
[Voltage Range]   1.200V   1.160V   1.240V
[C Comp Corner]
C_comp   2.000pF   1.500pF   2.500pF
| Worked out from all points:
|   slope of the pulldown table from 0 to 0.18 V, typ, clamps not added: 226 ohm
|   slope of the pullup table from 0 to 0.18 V, typ, clamps not added: 204 ohm
|   GND clamp passes 1 mA (typ) near -0.50 V on its own axis
|   POWER clamp passes 1 mA (typ) near -0.45 V on its own axis
|   rising waveform, R_fixture 50.000, V_fixture 0.000: 20-80 % time 159ps typ, 177ps min, 149ps max; typ from 0 V to 0.223 V
|   rising waveform, R_fixture 50.000, V_fixture 0.600: 20-80 % time 145ps typ, 162ps min, 136ps max; typ from 0.492 V to 0.717 V
|   falling waveform, R_fixture 50.000, V_fixture 0.600: 20-80 % time 140ps typ, 153ps min, 133ps max; typ from 0.717 V to 0.492 V
|   falling waveform, R_fixture 50.000, V_fixture 0.000: 20-80 % time 136ps typ, 147ps min, 130ps max; typ from 0.223 V to 0 V
[Pulldown]
|Voltage   I(typ)   I(min)   I(max)
-1.2V     -146mA     -169.1mA   -132.5mA
-1.089V   -75.55mA   -99.39mA   -62.36mA
-1.015V   -41.24mA   -61.24mA   -33.1mA
-904mV    -18.11mA   -25.13mA   -19.28mA
-793mV    -12.1mA    -12.23mA   -14.42mA
-349mV    -1.689mA   -1.81mA    -1.609mA
1.575V    6.943mA    7.179mA    6.507mA
2.019V    18.39mA    22.25mA    19.32mA
2.13V     25.73mA    46.11mA    24.21mA
2.204V    40.77mA    77.2mA     29.17mA
2.315V    92.48mA    141.3mA    58mA
2.4V      147.6mA    198.5mA    106.6mA
[Pullup]
|Voltage   I(typ)   I(min)   I(max)
-1.2V     123.8mA    138.9mA    117.2mA
-1.078V   61.01mA    74.06mA    58.07mA
-967mV    35.15mA    38.61mA    39.48mA
-634mV    8.595mA    8.918mA    9.646mA
-412mV    1.865mA    2.033mA    1.66mA
1.586V    -6.581mA   -6.724mA   -6.124mA
1.771V    -10.36mA   -12.6mA    -8.666mA
1.993V    -25.56mA   -27.86mA   -25.01mA
2.104V    -35.7mA    -41.75mA   -36.22mA
2.215V    -51.45mA   -74.44mA   -48.53mA
2.326V    -93.53mA   -133.6mA   -70.45mA
2.4V      -139.1mA   -182.9mA   -105.8mA
[GND_clamp]
|Voltage   I(typ)   I(min)   I(max)
-1.2V     -122.7mA   -137.7mA   -116mA
-1.15V    -93.48mA   -108.7mA   -87.06mA
-1.1V     -68.68mA   -82.93mA   -64.19mA
-1.05V    -50.06mA   -61.34mA   -49.53mA
-1V       -38.15mA   -44.88mA   -41.24mA
-950mV    -30.91mA   -33.54mA   -35.51mA
-900mV    -25.81mA   -26.1mA    -30.49mA
-825mV    -19.48mA   -18.8mA    -23.39mA
-700mV    -10.29mA   -10.29mA   -12.48mA
-575mV    -3.418mA   -4.142mA   -4.045mA
-450mV    -323.4uA   -814.3uA   -268.3uA
1.2V      0A         0A         0A
[POWER_clamp]
|Voltage   I(typ)   I(min)   I(max)
-1.175V   127.9mA    151.5mA    114.3mA
-1.125V   95.1mA     119.3mA    81.28mA
-1.1V     80mA       104.2mA    66.46mA
-1.05V    53.45mA    76.25mA    42.06mA
-1.025V   42.52mA    63.79mA    33.25mA
-975mV    26.42mA    42.64mA    22.65mA
-925mV    17.53mA    27.24mA    17.97mA
-875mV    13.15mA    17.46mA    15.37mA
-800mV    9.709mA    10.06mA    12.3mA
-625mV    4.479mA    4.015mA    6.021mA
-350mV    147.7uA    296.5uA    176.7uA
1.2V      0A         0A         0A
[Ramp]
| variable   typ   min   max
dV/dt_r   0.134/0.159n   0.123/0.178n   0.131/0.149n
dV/dt_f   0.129/0.150n   0.123/0.170n   0.126/0.140n
R_load = 50.000
[Rising Waveform]
R_fixture = 50.000
V_fixture = 0.000
V_fixture_min = 0.000
V_fixture_max = 0.000
|  time   V(typ)   V(min)   V(max)
0s        2.732uV    13.52uV    1.192uV
390ps     317uV      161.4uV    720.4uV
420ps     -1.505uV   241.9uV    22.68mV
497ps     3.549mV    -31.43uV   113.6mV
581ps     90.24mV    -409.7uV   171.8mV
675ps     166.2mV    67.17mV    199.5mV
796ps     204.8mV    152.7mV    212.1mV
887ps     215.2mV    181.4mV    215.4mV
1.016ns   220.7mV    197.5mV    217.1mV
10ns      223.1mV    205.3mV    217.9mV
[Rising Waveform]
R_fixture = 50.000
V_fixture = 0.600
V_fixture_min = 0.583
V_fixture_max = 0.619
|  time   V(typ)   V(min)   V(max)
0s        491.6mV    479.1mV    513.5mV
395ps     491.9mV    479.3mV    514.9mV
420ps     491.7mV    479.3mV    532.9mV
497ps     500.3mV    479.1mV    638mV
569ps     584.4mV    482mV      687.7mV
611ps     628.6mV    500.8mV    703.4mV
651ps     657.4mV    542.5mV    713.2mV
766ps     697.6mV    635.2mV    726.5mV
985ps     714.5mV    682.1mV    731.9mV
10ns      716.9mV    689.7mV    732.7mV
[Falling Waveform]
R_fixture = 50.000
V_fixture = 0.600
V_fixture_min = 0.583
V_fixture_max = 0.619
|  time   V(typ)   V(min)   V(max)
0s        716.9mV    689.7mV    732.7mV
388ps     716.9mV    689.6mV    731.8mV
491ps     711.1mV    690.1mV    606.3mV
565ps     617.3mV    688.7mV    556.4mV
599ps     580.3mV    671.2mV    543.8mV
643ps     548.4mV    624.2mV    532.9mV
697ps     524.9mV    567.8mV    524.8mV
754ps     510.8mV    530.9mV    519.9mV
964ps     494.3mV    486.9mV    514.4mV
10ns      491.6mV    479.1mV    513.5mV
[Falling Waveform]
R_fixture = 50.000
V_fixture = 0.000
V_fixture_min = 0.000
V_fixture_max = 0.000
|  time   V(typ)   V(min)   V(max)
0s        223.1mV    205.3mV    217.9mV
386ps     223.3mV    205.2mV    217.4mV
417ps     223.8mV    205.3mV    194.8mV
487ps     218mV      206mV      96.01mV
561ps     127mV      204.5mV    43.81mV
634ps     58.68mV    150mV      20.82mV
697ps     31.13mV    82.86mV    11.11mV
747ps     19.05mV    50.31mV    6.806mV
954ps     2.756mV    7.324mV    991.8uV
10ns      2.732uV    13.52uV    1.192uV
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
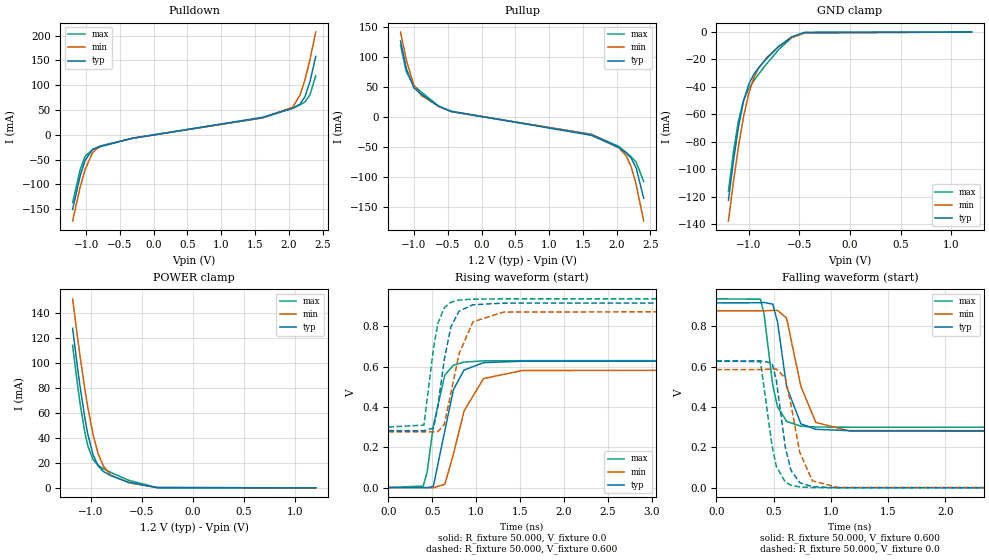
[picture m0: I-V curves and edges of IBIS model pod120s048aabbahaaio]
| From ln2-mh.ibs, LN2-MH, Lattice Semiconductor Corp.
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|   Model pod120s048aabbahaaio
[Model] pod120s048aabbahaaio
| Clamp models do not include dynamic input termination. Please refer to
| the pod120axxxaabbahaain model for input termination.
Model_type I/O
Polarity   Non-Inverting
Enable   Active-Low
Vinl =  0.800V
Vinh =  1.000V
Vmeas =  0.600V
Cref =  20.000pF
Rref =  50.000
Vref =  0.600V
C_comp   2.000pF   1.500pF   2.500pF
[Temperature Range]   25.000   0.125k   -40.000
[Voltage Range]   1.200V   1.160V   1.240V
[C Comp Corner]
C_comp   2.000pF   1.500pF   2.500pF
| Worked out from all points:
|   slope of the pulldown table from 0 to 0.18 V, typ, clamps not added: 44.5 ohm
|   slope of the pullup table from 0 to 0.18 V, typ, clamps not added: 44.9 ohm
|   GND clamp passes 1 mA (typ) near -0.50 V on its own axis
|   POWER clamp passes 1 mA (typ) near -0.45 V on its own axis
|   rising waveform, R_fixture 50.000, V_fixture 0.0: 20-80 % time 169ps typ, 226ps min, 137ps max; typ from 0 V to 0.627 V
|   rising waveform, R_fixture 50.000, V_fixture 0.600: 20-80 % time 142ps typ, 190ps min, 115ps max; typ from 0.282 V to 0.916 V
|   falling waveform, R_fixture 50.000, V_fixture 0.600: 20-80 % time 105ps typ, 139ps min, 92.4ps max; typ from 0.916 V to 0.282 V
|   falling waveform, R_fixture 50.000, V_fixture 0.0: 20-80 % time 98.6ps typ, 124ps min, 90.5ps max; typ from 0.627 V to 0 V
[Pulldown]
|Voltage   I(typ)   I(min)   I(max)
-1.2V     -150.9mA   -174mA     -137.1mA
-1.089V   -83.5mA    -106.2mA   -70.74mA
-1.015V   -51.59mA   -69.99mA   -43.42mA
-904mV    -29.33mA   -35.67mA   -29.64mA
-793mV    -22.9mA    -22.74mA   -24.33mA
-312mV    -7.083mA   -7.066mA   -6.683mA
1.612V    35.31mA    34.52mA    34mA
2.056V    53.27mA    55.43mA    53.91mA
2.167V    61.89mA    80.22mA    60.44mA
2.241V    77.15mA    111.6mA    66.35mA
2.315V    107.9mA    152.7mA    80.79mA
2.4V      158.2mA    207.4mA    119.5mA
[Pullup]
|Voltage   I(typ)   I(min)   I(max)
-1.2V     127.1mA    142mA      120mA
-1.115V   81.3mA     95.43mA    75.78mA
-1.004V   48.86mA    53.76mA    52.31mA
-893mV    38.28mA    36.21mA    42.01mA
-634mV    18.06mA    17.76mA    18.21mA
-449mV    9.831mA    9.596mA    8.994mA
1.623V    -30.34mA   -29.2mA    -28.61mA
2.03V     -50.48mA   -50.95mA   -48.79mA
2.141V    -59.83mA   -64.48mA   -59mA
2.215V    -68.36mA   -82.83mA   -66.26mA
2.289V    -84.85mA   -112.4mA   -75.03mA
2.4V      -135.5mA   -173.4mA   -107.4mA
[GND_clamp]
|Voltage   I(typ)   I(min)   I(max)
-1.2V     -122.7mA   -137.7mA   -116mA
-1.15V    -93.48mA   -108.7mA   -87.06mA
-1.1V     -68.68mA   -82.93mA   -64.19mA
-1.05V    -50.06mA   -61.34mA   -49.53mA
-1V       -38.15mA   -44.88mA   -41.24mA
-950mV    -30.91mA   -33.54mA   -35.51mA
-900mV    -25.81mA   -26.1mA    -30.49mA
-825mV    -19.48mA   -18.8mA    -23.39mA
-700mV    -10.29mA   -10.29mA   -12.48mA
-575mV    -3.418mA   -4.142mA   -4.045mA
-450mV    -323.4uA   -814.3uA   -268.3uA
1.2V      0A         0A         0A
[POWER_clamp]
|Voltage   I(typ)   I(min)   I(max)
-1.175V   127.9mA    151.5mA    114.3mA
-1.125V   95.1mA     119.3mA    81.28mA
-1.1V     80mA       104.2mA    66.46mA
-1.05V    53.45mA    76.25mA    42.06mA
-1.025V   42.52mA    63.79mA    33.25mA
-975mV    26.42mA    42.64mA    22.65mA
-925mV    17.53mA    27.24mA    17.97mA
-875mV    13.15mA    17.46mA    15.37mA
-800mV    9.709mA    10.06mA    12.3mA
-625mV    4.479mA    4.015mA    6.021mA
-350mV    147.7uA    296.5uA    176.7uA
1.2V      0A         0A         0A
[Ramp]
| variable   typ   min   max
dV/dt_r   0.376/0.169n   0.351/0.226n   0.378/0.138n
dV/dt_f   0.380/0.119n   0.365/0.164n   0.383/96.871p
R_load = 50.000
[Rising Waveform]
R_fixture= 50.000
V_fixture= 0.0
V_fixture_min= 0.0
V_fixture_max= 0.0
|time   V(typ)   V(min)   V(max)
0s        1.292uV    7.005uV    589.2nV
397ps     -239uV     71.17uV    7.302mV
442ps     -1.458mV   51.83uV    76.87mV
513ps     6.253mV    -1.073mV   307.5mV
643ps     282mV      16.23mV    558.2mV
742ps     485.9mV    166.3mV    606.6mV
862ps     582.9mV    379.4mV    622.5mV
1.084ns   619.5mV    540.5mV    628.3mV
1.524ns   626.8mV    580.5mV    629.3mV
10ns      627.3mV    585.3mV    629.4mV
[Rising Waveform]
R_fixture= 50.000
V_fixture= 0.600
V_fixture_min= 0.583
V_fixture_max= 0.619
|time   V(typ)   V(min)   V(max)
0s        282.5mV    276.8mV    300.3mV
405ps     282.1mV    276.9mV    309.7mV
514ps     294.8mV    276.3mV    690.4mV
564ps     403.5mV    277.5mV    813.4mV
637ps     635.1mV    313.3mV    891.5mV
712ps     796mV      466.6mV    919mV
804ps     874.5mV    662.3mV    930mV
964ps     906.9mV    822.2mV    934.6mV
1.314ns   915mV      870.6mV    935.9mV
10ns      915.9mV    876.6mV    936mV
[Falling Waveform]
R_fixture= 50.000
V_fixture= 0.600
V_fixture_min= 0.583
V_fixture_max= 0.619
|time   V(typ)   V(min)   V(max)
0s        915.9mV    876.6mV    936mV
386ps     916.6mV    876.7mV    934.6mV
417ps     918.1mV    876.9mV    862.7mV
493ps     910.1mV    878.9mV    508.9mV
535ps     821.4mV    879.4mV    401.6mV
614ps     500.9mV    840.1mV    328.9mV
739ps     316.9mV    502.5mV    305.3mV
869ps     289.9mV    324mV      301.4mV
1.168ns   283.2mV    281.1mV    300.4mV
10ns      282.5mV    276.8mV    300.3mV
[Falling Waveform]
R_fixture= 50.000
V_fixture= 0.0
V_fixture_min= 0.0
V_fixture_max= 0.0
|time   V(typ)   V(min)   V(max)
0s        627.3mV    585.3mV    629.4mV
386ps     628.9mV    585.5mV    624.5mV
487ps     618.4mV    588.7mV    208.5mV
525ps     531.3mV    589mV      105.4mV
603ps     199.9mV    543.9mV    28.35mV
653ps     85.88mV    409.3mV    13.05mV
729ps     25.47mV    176.1mV    4.406mV
839ps     5.581mV    34.81mV    1.117mV
1.063ns   599.6uV    2.461mV    139.9uV
10ns      1.309uV    7.016uV    608.3nV
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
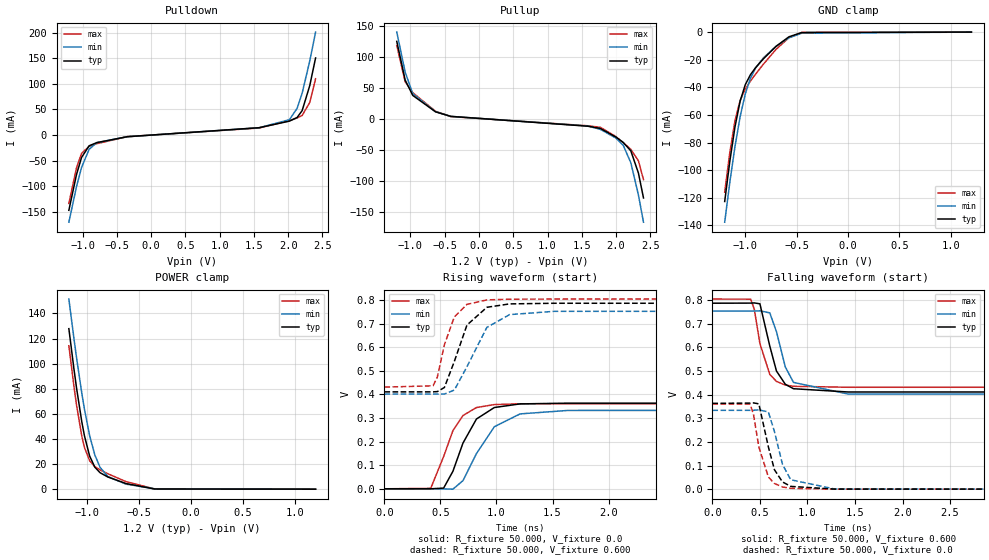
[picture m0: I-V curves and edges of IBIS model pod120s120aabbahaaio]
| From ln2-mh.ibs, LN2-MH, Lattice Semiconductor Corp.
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|   Model pod120s120aabbahaaio
[Model] pod120s120aabbahaaio
| Clamp models do not include dynamic input termination. Please refer to
| the pod120axxxaabbahaain model for input termination.
Model_type I/O
Polarity   Non-Inverting
Enable   Active-Low
Vinl =  0.800V
Vinh =  1.000V
Vmeas =  0.600V
Cref =  20.000pF
Rref =  50.000
Vref =  0.600V
C_comp   2.000pF   1.500pF   2.500pF
[Temperature Range]   25.000   0.125k   -40.000
[Voltage Range]   1.200V   1.160V   1.240V
[C Comp Corner]
C_comp   2.000pF   1.500pF   2.500pF
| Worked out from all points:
|   slope of the pulldown table from 0 to 0.18 V, typ, clamps not added: 108 ohm
|   slope of the pullup table from 0 to 0.18 V, typ, clamps not added: 110 ohm
|   GND clamp passes 1 mA (typ) near -0.50 V on its own axis
|   POWER clamp passes 1 mA (typ) near -0.45 V on its own axis
|   rising waveform, R_fixture 50.000, V_fixture 0.0: 20-80 % time 202ps typ, 251ps min, 175ps max; typ from 0 V to 0.363 V
|   rising waveform, R_fixture 50.000, V_fixture 0.600: 20-80 % time 164ps typ, 211ps min, 137ps max; typ from 0.411 V to 0.787 V
|   falling waveform, R_fixture 50.000, V_fixture 0.600: 20-80 % time 132ps typ, 154ps min, 121ps max; typ from 0.787 V to 0.411 V
|   falling waveform, R_fixture 50.000, V_fixture 0.0: 20-80 % time 123ps typ, 138ps min, 116ps max; typ from 0.363 V to 0 V
[Pulldown]
|Voltage   I(typ)   I(min)   I(max)
-1.2V     -147.3mA   -170.5mA   -133.8mA
-1.089V   -77.66mA   -101.2mA   -64.58mA
-1.015V   -43.96mA   -63.56mA   -35.86mA
-904mV    -21.07mA   -27.91mA   -22.06mA
-793mV    -14.95mA   -15mA      -17.08mA
-349mV    -3.365mA   -3.453mA   -3.218mA
1.575V    14.23mA    14.15mA    13.66mA
2.019V    27.14mA    29.91mA    28.05mA
2.13V     34.19mA    52.06mA    33.31mA
2.204V    47.64mA    81.78mA    38.11mA
2.315V    96.57mA    144.6mA    63.67mA
2.4V      150.6mA    201.2mA    110mA
[Pullup]
|Voltage   I(typ)   I(min)   I(max)
-1.2V     124.8mA    139.8mA    118mA
-1.078V   62.49mA    75.36mA    59.56mA
-967mV    37.57mA    40.48mA    41.98mA
-634mV    11.06mA    11.21mA    11.91mA
-412mV    3.733mA    3.741mA    3.415mA
1.586V    -12.11mA   -11.81mA   -11.44mA
1.771V    -15.73mA   -17.27mA   -13.95mA
1.993V    -29.36mA   -30.95mA   -28.52mA
2.104V    -38.42mA   -42.98mA   -38.57mA
2.215V    -51.91mA   -71.07mA   -49.55mA
2.326V    -87.84mA   -123.2mA   -68.05mA
2.4V      -128mA     -167.1mA   -98.35mA
[GND_clamp]
|Voltage   I(typ)   I(min)   I(max)
-1.2V     -122.7mA   -137.7mA   -116mA
-1.15V    -93.48mA   -108.7mA   -87.06mA
-1.1V     -68.68mA   -82.93mA   -64.19mA
-1.05V    -50.06mA   -61.34mA   -49.53mA
-1V       -38.15mA   -44.88mA   -41.24mA
-950mV    -30.92mA   -33.54mA   -35.51mA
-900mV    -25.81mA   -26.1mA    -30.49mA
-825mV    -19.48mA   -18.8mA    -23.39mA
-700mV    -10.29mA   -10.29mA   -12.48mA
-575mV    -3.418mA   -4.142mA   -4.045mA
-450mV    -323.4uA   -814.3uA   -268.3uA
1.2V      0A         0A         0A
[POWER_clamp]
|Voltage   I(typ)   I(min)   I(max)
-1.175V   127.9mA    151.5mA    114.3mA
-1.125V   95.1mA     119.3mA    81.28mA
-1.1V     80mA       104.2mA    66.46mA
-1.05V    53.45mA    76.25mA    42.06mA
-1.025V   42.52mA    63.79mA    33.25mA
-975mV    26.42mA    42.64mA    22.65mA
-925mV    17.53mA    27.24mA    17.97mA
-875mV    13.15mA    17.46mA    15.37mA
-800mV    9.709mA    10.06mA    12.3mA
-625mV    4.479mA    4.015mA    6.021mA
-350mV    147.7uA    296.5uA    176.7uA
1.2V      0A         0A         0A
[Ramp]
| variable   typ   min   max
dV/dt_r   0.218/0.202n   0.200/0.250n   0.217/0.175n
dV/dt_f   0.226/0.151n   0.215/0.184n   0.225/0.134n
R_load = 50.000
[Rising Waveform]
R_fixture= 50.000
V_fixture= 0.0
V_fixture_min= 0.0
V_fixture_max= 0.0
|time   V(typ)   V(min)   V(max)
0s        1.991uV    10.66uV    896.8nV
413ps     9.082uV    181.7uV    2.024mV
528ps     3.028mV    -438uV     136.6mV
611ps     74.21mV    -1.511mV   246.5mV
701ps     194mV      34.66mV    310.7mV
821ps     295.9mV    149.3mV    344.5mV
981ps     344.7mV    263.3mV    357.1mV
1.211ns   360mV      317.6mV    360.4mV
1.637ns   363mV      332.2mV    360.9mV
10ns      363.1mV    333.6mV    360.9mV
[Rising Waveform]
R_fixture= 50.000
V_fixture= 0.600
V_fixture_min= 0.583
V_fixture_max= 0.619
|time   V(typ)   V(min)   V(max)
0s        411mV      401.5mV    431.1mV
434ps     411mV      401.7mV    436.7mV
472ps     412.1mV    401.6mV    473.8mV
535ps     429.6mV    401.7mV    610.8mV
624ps     540.3mV    418.7mV    729mV
736ps     694mV      517.2mV    781.8mV
914ps     769.5mV    684.4mV    800.8mV
1.117ns   783.9mV    738.5mV    803.9mV
1.516ns   786.6mV    752.4mV    804.4mV
10ns      786.8mV    753.6mV    804.4mV
[Falling Waveform]
R_fixture= 50.000
V_fixture= 0.600
V_fixture_min= 0.583
V_fixture_max= 0.619
|time   V(typ)   V(min)   V(max)
0s        786.8mV    753.6mV    804.4mV
403ps     787.3mV    753.7mV    804mV
441ps     788.1mV    753.8mV    761.7mV
500ps     784.4mV    754.7mV    616mV
604ps     605.5mV    746mV      485.7mV
674ps     500mV      666.4mV    456.1mV
767ps     444mV      517.2mV    440.5mV
853ps     425mV      451.8mV    435.2mV
1.427ns   411.2mV    402.6mV    431.2mV
10ns      411mV      401.5mV    431.1mV
[Falling Waveform]
R_fixture= 50.000
V_fixture= 0.0
V_fixture_min= 0.0
V_fixture_max= 0.0
|time   V(typ)   V(min)   V(max)
0s        363.1mV    333.6mV    360.9mV
397ps     364.2mV    333.6mV    359.9mV
432ps     365.1mV    334mV      317.7mV
489ps     360.9mV    335.5mV    178.7mV
589ps     178.8mV    326.8mV    51.4mV
653ps     82.09mV    243.7mV    24.07mV
737ps     30.79mV    105.5mV    9.256mV
824ps     11.73mV    39.77mV    3.614mV
1.287ns   239.3uV    652.6uV    90.73uV
10ns      2.007uV    10.68uV    917.6nV
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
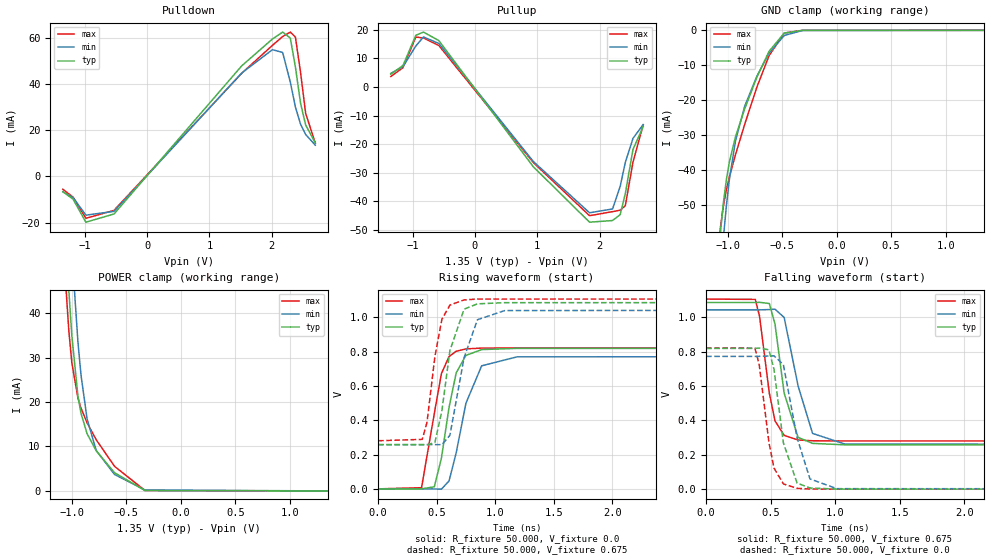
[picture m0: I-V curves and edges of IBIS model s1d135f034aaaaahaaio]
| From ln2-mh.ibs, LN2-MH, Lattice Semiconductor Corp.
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|   Model s1d135f034aaaaahaaio
[Model] s1d135f034aaaaahaaio
| Clamp models do not include dynamic input termination. Please refer to
| the s1d135axxxaaaaahaain model for input termination.
Model_type I/O
Polarity   Non-Inverting
Enable   Active-Low
Vinl =  0.575V
Vinh =  0.775V
Vmeas =  0.675V
Cref =  30.000pF
Rref =  50.000
Vref =  0.675V
C_comp   2.000pF   1.500pF   2.500pF
[Temperature Range]   25.000   0.125k   -40.000
[Voltage Range]   1.350V   1.310V   1.390V
[C Comp Corner]
C_comp   2.000pF   1.500pF   2.500pF
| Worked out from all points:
|   slope of the pulldown table from 0 to 0.203 V, typ, clamps not added: 30.8 ohm
|   slope of the pullup table from 0 to 0.203 V, typ, clamps not added: 31.9 ohm
|   GND clamp passes 1 mA (typ) near -0.49 V on its own axis
|   POWER clamp passes 1 mA (typ) near -0.45 V on its own axis
|   rising waveform, R_fixture 50.000, V_fixture 0.0: 20-80 % time 121ps typ, 147ps min, 108ps max; typ from 0 V to 0.82 V
|   rising waveform, R_fixture 50.000, V_fixture 0.675: 20-80 % time 107ps typ, 127ps min, 98.4ps max; typ from 0.258 V to 1.09 V
|   falling waveform, R_fixture 50.000, V_fixture 0.675: 20-80 % time 95.4ps typ, 123ps min, 90.5ps max; typ from 1.09 V to 0.258 V
|   falling waveform, R_fixture 50.000, V_fixture 0.0: 20-80 % time 90.8ps typ, 115ps min, 87.9ps max; typ from 0.82 V to 0 V
[Pulldown]
|Voltage   I(typ)   I(min)   I(max)
-1.35V    -6.62mA    -6.672mA   -5.576mA
-1.186V   -9.86mA    -9.169mA   -8.97mA
-981mV    -19.79mA   -16.75mA   -18.11mA
-530mV    -16.24mA   -15.11mA   -14.68mA
1.52V     47.81mA    44.72mA    44.59mA
2.012V    59.39mA    54.77mA    56.64mA
2.176V    62.38mA    53.58mA    60.45mA
2.299V    59.81mA    40.78mA    62.37mA
2.381V    47.31mA    29.97mA    60.23mA
2.463V    31.69mA    22.6mA     45.04mA
2.545V    22.23mA    18.12mA    27.28mA
2.7V      14.5mA     13.51mA    14.43mA
[Pullup]
|Voltage   I(typ)   I(min)   I(max)
-1.35V    4.51mA     4.757mA    3.684mA
-1.154V   7.538mA    7.14mA     6.787mA
-949mV    18.09mA    14.34mA    17.47mA
-826mV    19.22mA    17.51mA    17.17mA
-580mV    16.24mA    15.26mA    14.54mA
937mV     -27.93mA   -26.08mA   -26.45mA
1.839V    -47.32mA   -44.03mA   -45.05mA
2.208V    -46.74mA   -42.69mA   -43.62mA
2.331V    -44.67mA   -34.74mA   -43.14mA
2.413V    -37.28mA   -26.36mA   -41.53mA
2.536V    -21.82mA   -17.98mA   -26.29mA
2.7V      -13.83mA   -13.14mA   -13.25mA
[GND_clamp]
|Voltage   I(typ)   I(min)   I(max)
-1.35V    -225.5mA   -236.8mA   -221.1mA
-1.07V    -58.41mA   -70.65mA   -56.85mA
-1.042V   -49.59mA   -59.67mA   -50.43mA
-1.014V   -42.81mA   -50.34mA   -45.7mA
-986mV    -37.69mA   -42.66mA   -41.93mA
-930mV    -30.47mA   -31.63mA   -35.59mA
-846mV    -22.52mA   -21.77mA   -26.96mA
-734mV    -13.45mA   -13.14mA   -16.29mA
-622mV    -6.019mA   -6.567mA   -7.264mA
-482mV    -782.7uA   -1.472mA   -781.2uA
-314mV    -4.342uA   -42.56uA   -1.145uA
1.35V     0A         0A         0A
[POWER_clamp]
|Voltage   I(typ)   I(min)   I(max)
-1.338V   248.4mA    267.8mA    238.2mA
-1.086V   72.51mA    96.3mA     59.73mA
-1.058V   57.87mA    80.82mA    46.5mA
-1.03V    45.22mA    66.59mA    36.14mA
-1.002V   34.89mA    53.83mA    28.81mA
-946mV    21.36mA    33.5mA     20.89mA
-918mV    17.49mA    26.1mA     18.65mA
-862mV    12.87mA    16.19mA    15.32mA
-778mV    9.039mA    9.085mA    11.51mA
-610mV    4.102mA    3.705mA    5.539mA
-330mV    85.2uA     208uA      91.66uA
1.35V     0A         0A         0A
[Ramp]
| variable   typ   min   max
dV/dt_r   0.492/0.121n   0.464/0.148n   0.493/0.108n
dV/dt_f   0.500/0.105n   0.476/0.139n   0.497/94.389p
R_load = 50.000
[Rising Waveform]
R_fixture= 50.000
V_fixture= 0.0
V_fixture_min= 0.0
V_fixture_max= 0.0
|time   V(typ)   V(min)   V(max)
0s        1.092uV    6.154uV    504.8nV
370ps     59.35uV    42.65uV    6.714mV
479ps     12.16mV    -409.4uV   439.5mV
540ps     180.2mV    -1.745mV   673mV
605ps     476.4mV    46.58mV    772.1mV
666ps     676.8mV    210.8mV    802.5mV
749ps     778.5mV    499.7mV    816.3mV
883ps     812.4mV    717.6mV    821.1mV
1.185ns   819.4mV    770mV      821.8mV
10ns      819.5mV    773.1mV    821.8mV
[Rising Waveform]
R_fixture= 50.000
V_fixture= 0.675
V_fixture_min= 0.656
V_fixture_max= 0.696
|time   V(typ)   V(min)   V(max)
0s        257.6mV    258.3mV    280.7mV
376ps     257.6mV    258.4mV    288.7mV
417ps     257.1mV    258.4mV    389.5mV
484ps     270.4mV    257.9mV    771.9mV
544ps     456.5mV    258mV      989.3mV
612ps     806.2mV    312.1mV    1.072V
733ps     1.048V     764.6mV    1.102V
847ps     1.079V     986.5mV    1.107V
1.081ns   1.086V     1.04V      1.107V
10ns      1.087V     1.044V     1.107V
[Falling Waveform]
R_fixture= 50.000
V_fixture= 0.675
V_fixture_min= 0.656
V_fixture_max= 0.696
|time   V(typ)   V(min)   V(max)
0s        1.087V     1.044V     1.107V
381ps     1.087V     1.044V     1.105V
414ps     1.088V     1.044V     1.008V
490ps     1.081V     1.046V     559.1mV
534ps     961mV      1.048V     397.6mV
605ps     559.3mV    1V         313.1mV
713ps     301.6mV    601mV      286.4mV
825ps     266.6mV    324.7mV    281.8mV
1.076ns   258.2mV    262.6mV    280.8mV
10ns      257.6mV    258.3mV    280.7mV
[Falling Waveform]
R_fixture= 50.000
V_fixture= 0.0
V_fixture_min= 0.0
V_fixture_max= 0.0
|time   V(typ)   V(min)   V(max)
0s        819.5mV    773.1mV    821.8mV
379ps     820mV      773.2mV    820.4mV
412ps     821.7mV    773.4mV    723.7mV
487ps     811.3mV    775.5mV    272.3mV
526ps     698.7mV    776.6mV    123.2mV
599ps     269.7mV    725.2mV    30.4mV
705ps     35.37mV    299.3mV    4.893mV
805ps     7.026mV    59.57mV    925.8uV
1.013ns   372.3uV    2.979mV    -17.28uV
10ns      1.092uV    6.141uV    510.2nV
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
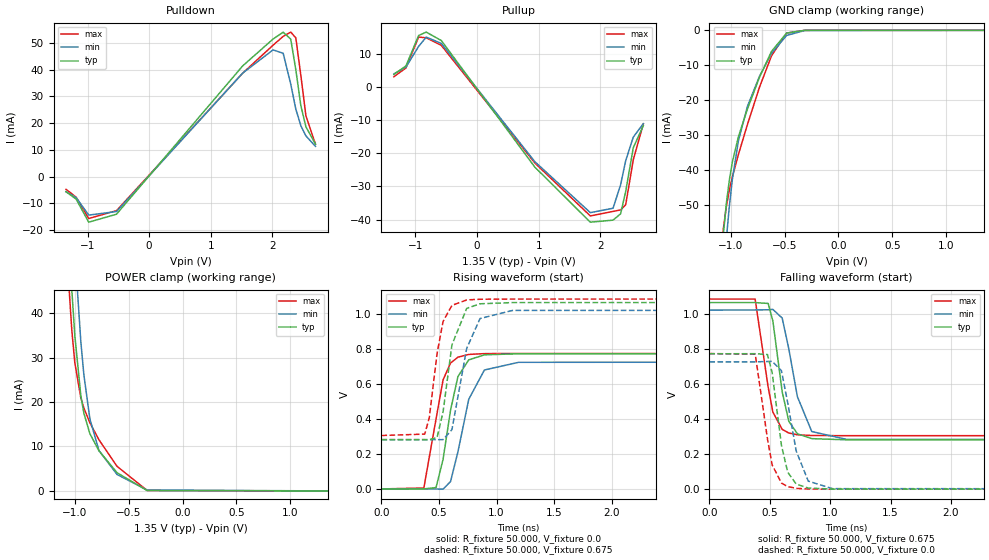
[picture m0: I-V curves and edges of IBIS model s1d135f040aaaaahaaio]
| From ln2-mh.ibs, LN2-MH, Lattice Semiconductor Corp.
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|   Model s1d135f040aaaaahaaio
[Model] s1d135f040aaaaahaaio
| Clamp models do not include dynamic input termination. Please refer to
| the s1d135axxxaaaaahaain model for input termination.
Model_type I/O
Polarity   Non-Inverting
Enable   Active-Low
Vinl =  0.575V
Vinh =  0.775V
Vmeas =  0.675V
Cref =  30.000pF
Rref =  50.000
Vref =  0.675V
C_comp   2.000pF   1.500pF   2.500pF
[Temperature Range]   25.000   0.125k   -40.000
[Voltage Range]   1.350V   1.310V   1.390V
[C Comp Corner]
C_comp   2.000pF   1.500pF   2.500pF
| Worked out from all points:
|   slope of the pulldown table from 0 to 0.203 V, typ, clamps not added: 35.6 ohm
|   slope of the pullup table from 0 to 0.203 V, typ, clamps not added: 36.9 ohm
|   GND clamp passes 1 mA (typ) near -0.49 V on its own axis
|   POWER clamp passes 1 mA (typ) near -0.45 V on its own axis
|   rising waveform, R_fixture 50.000, V_fixture 0.0: 20-80 % time 121ps typ, 149ps min, 110ps max; typ from 0 V to 0.771 V
|   rising waveform, R_fixture 50.000, V_fixture 0.675: 20-80 % time 104ps typ, 126ps min, 97.7ps max; typ from 0.281 V to 1.06 V
|   falling waveform, R_fixture 50.000, V_fixture 0.675: 20-80 % time 98.6ps typ, 127ps min, 93.9ps max; typ from 1.06 V to 0.281 V
|   falling waveform, R_fixture 50.000, V_fixture 0.0: 20-80 % time 94.5ps typ, 119ps min, 91.9ps max; typ from 0.771 V to 0 V
[Pulldown]
|Voltage   I(typ)   I(min)   I(max)
-1.35V    -5.632mA   -5.674mA   -4.767mA
-1.186V   -8.406mA   -7.822mA   -7.672mA
-981mV    -17.04mA   -14.39mA   -15.66mA
-530mV    -14.05mA   -13.06mA   -12.73mA
1.52V     41.41mA    38.71mA    38.69mA
2.012V    51.41mA    47.36mA    49.11mA
2.176V    53.96mA    46.1mA     52.41mA
2.299V    51.38mA    34.57mA    54.01mA
2.381V    39.95mA    25.26mA    51.84mA
2.463V    26.52mA    19.01mA    37.82mA
2.545V    18.62mA    15.22mA    22.73mA
2.7V      12.16mA    11.31mA    12.13mA
[Pullup]
|Voltage   I(typ)   I(min)   I(max)
-1.35V    3.793mA    3.989mA    3.114mA
-1.154V   6.389mA    6.04mA     5.775mA
-949mV    15.54mA    12.26mA    15.08mA
-826mV    16.58mA    15.06mA    14.84mA
-580mV    14.02mA    13.16mA    12.57mA
937mV     -24.15mA   -22.51mA   -22.91mA
1.839V    -40.79mA   -37.91mA   -38.9mA
2.208V    -40.17mA   -36.58mA   -37.54mA
2.331V    -38.24mA   -29.47mA   -37.08mA
2.413V    -31.55mA   -22.24mA   -35.53mA
2.536V    -18.32mA   -15.13mA   -21.98mA
2.7V      -11.62mA   -11.04mA   -11.11mA
[GND_clamp]
|Voltage   I(typ)   I(min)   I(max)
-1.35V    -225.5mA   -236.8mA   -221.1mA
-1.07V    -58.4mA    -70.65mA   -56.85mA
-1.042V   -49.58mA   -59.67mA   -50.43mA
-1.014V   -42.81mA   -50.34mA   -45.7mA
-986mV    -37.69mA   -42.66mA   -41.93mA
-930mV    -30.47mA   -31.63mA   -35.58mA
-846mV    -22.52mA   -21.77mA   -26.96mA
-734mV    -13.45mA   -13.14mA   -16.28mA
-622mV    -6.019mA   -6.567mA   -7.264mA
-482mV    -782.7uA   -1.472mA   -781.2uA
-314mV    -4.342uA   -42.56uA   -1.145uA
1.35V     0A         0A         0A
[POWER_clamp]
|Voltage   I(typ)   I(min)   I(max)
-1.338V   248.4mA    267.8mA    238.2mA
-1.086V   72.51mA    96.3mA     59.73mA
-1.058V   57.87mA    80.82mA    46.5mA
-1.03V    45.22mA    66.59mA    36.14mA
-1.002V   34.89mA    53.83mA    28.81mA
-946mV    21.36mA    33.5mA     20.89mA
-918mV    17.49mA    26.1mA     18.65mA
-862mV    12.87mA    16.19mA    15.32mA
-778mV    9.039mA    9.085mA    11.51mA
-610mV    4.102mA    3.705mA    5.539mA
-330mV    85.2uA     208uA      91.66uA
1.35V     0A         0A         0A
[Ramp]
| variable   typ   min   max
dV/dt_r   0.463/0.121n   0.435/0.149n   0.464/0.110n
dV/dt_f   0.472/0.108n   0.448/0.144n   0.469/97.035p
R_load = 50.000
[Rising Waveform]
R_fixture= 50.000
V_fixture= 0.0
V_fixture_min= 0.0
V_fixture_max= 0.0
|time   V(typ)   V(min)   V(max)
0s        1.215uV    6.808uV    559nV
368ps     64.76uV    46.44uV    5.1mV
474ps     7.79mV     -312uV     399mV
535ps     168.9mV    -1.4mV     621.9mV
600ps     449.9mV    42.47mV    718.2mV
664ps     641.1mV    211.4mV    751.4mV
758ps     736.1mV    511.5mV    767.1mV
894ps     764.9mV    678.5mV    771.8mV
1.191ns   771.1mV    722.2mV    772.5mV
10ns      771.2mV    725.1mV    772.5mV
[Rising Waveform]
R_fixture= 50.000
V_fixture= 0.675
V_fixture_min= 0.656
V_fixture_max= 0.696
|time   V(typ)   V(min)   V(max)
0s        280.9mV    281.2mV    304.7mV
376ps     280.9mV    281.2mV    312.7mV
415ps     280.4mV    281.2mV    405.4mV
483ps     293.7mV    280.8mV    772.8mV
535ps     439.4mV    281.2mV    955.3mV
612ps     822mV      338.4mV    1.047V
740ps     1.03V      801.6mV    1.078V
856ps     1.056V     972mV      1.082V
1.137ns   1.063V     1.018V     1.083V
10ns      1.063V     1.021V     1.083V
[Falling Waveform]
R_fixture= 50.000
V_fixture= 0.675
V_fixture_min= 0.656
V_fixture_max= 0.696
|time   V(typ)   V(min)   V(max)
0s        1.063V     1.02V      1.083V
379ps     1.063V     1.021V     1.083V
487ps     1.058V     1.022V     580.7mV
526ps     957.5mV    1.024V     439mV
603ps     554.5mV    974.7mV    340.7mV
658ps     386.6mV    798.8mV    319.8mV
729ps     315.6mV    526.6mV    309.8mV
848ps     287.8mV    328.2mV    305.6mV
1.136ns   281.1mV    283.7mV    304.7mV
10ns      280.9mV    281.2mV    304.7mV
[Falling Waveform]
R_fixture= 50.000
V_fixture= 0.0
V_fixture_min= 0.0
V_fixture_max= 0.0
|time   V(typ)   V(min)   V(max)
0s        771.2mV    725.1mV    772.5mV
380ps     771.8mV    725.2mV    769.1mV
481ps     766.9mV    727.3mV    287.2mV
520ps     663.6mV    728.4mV    138mV
597ps     248.9mV    674.7mV    34.68mV
649ps     96.24mV    491.1mV    14.62mV
719ps     29.1mV     217.3mV    4.729mV
819ps     6.379mV    45.78mV    930.4uV
1.019ns   348.7uV    3.079mV    -34.21uV
10ns      1.216uV    6.798uV    566.2nV
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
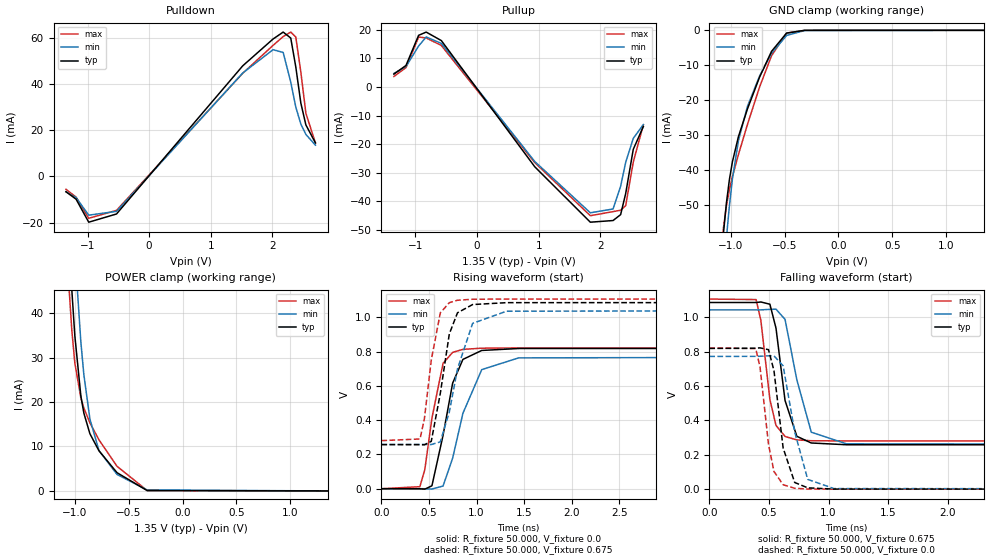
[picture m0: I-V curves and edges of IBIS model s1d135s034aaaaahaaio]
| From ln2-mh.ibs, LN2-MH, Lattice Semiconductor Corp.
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|   Model s1d135s034aaaaahaaio
[Model] s1d135s034aaaaahaaio
| Clamp models do not include dynamic input termination. Please refer to
| the s1d135axxxaaaaahaain model for input termination.
Model_type I/O
Polarity   Non-Inverting
Enable   Active-Low
Vinl =  0.575V
Vinh =  0.775V
Vmeas =  0.675V
Cref =  30.000pF
Rref =  50.000
Vref =  0.675V
C_comp   2.000pF   1.500pF   2.500pF
[Temperature Range]   25.000   0.125k   -40.000
[Voltage Range]   1.350V   1.310V   1.390V
[C Comp Corner]
C_comp   2.000pF   1.500pF   2.500pF
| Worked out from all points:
|   slope of the pulldown table from 0 to 0.203 V, typ, clamps not added: 30.8 ohm
|   slope of the pullup table from 0 to 0.203 V, typ, clamps not added: 31.9 ohm
|   GND clamp passes 1 mA (typ) near -0.49 V on its own axis
|   POWER clamp passes 1 mA (typ) near -0.45 V on its own axis
|   rising waveform, R_fixture 50.000, V_fixture 0.0: 20-80 % time 165ps typ, 224ps min, 133ps max; typ from 0 V to 0.82 V
|   rising waveform, R_fixture 50.000, V_fixture 0.675: 20-80 % time 138ps typ, 185ps min, 113ps max; typ from 0.258 V to 1.09 V
|   falling waveform, R_fixture 50.000, V_fixture 0.675: 20-80 % time 97.2ps typ, 126ps min, 87.5ps max; typ from 1.09 V to 0.258 V
|   falling waveform, R_fixture 50.000, V_fixture 0.0: 20-80 % time 89.4ps typ, 113ps min, 84.2ps max; typ from 0.82 V to 0 V
[Pulldown]
|Voltage   I(typ)   I(min)   I(max)
-1.35V    -6.62mA    -6.672mA   -5.576mA
-1.186V   -9.86mA    -9.169mA   -8.97mA
-981mV    -19.79mA   -16.75mA   -18.11mA
-530mV    -16.24mA   -15.11mA   -14.68mA
1.52V     47.81mA    44.72mA    44.59mA
2.012V    59.39mA    54.77mA    56.64mA
2.176V    62.38mA    53.58mA    60.45mA
2.299V    59.81mA    40.78mA    62.37mA
2.381V    47.31mA    29.97mA    60.23mA
2.463V    31.69mA    22.6mA     45.04mA
2.545V    22.23mA    18.12mA    27.28mA
2.7V      14.5mA     13.51mA    14.43mA
[Pullup]
|Voltage   I(typ)   I(min)   I(max)
-1.35V    4.51mA     4.757mA    3.684mA
-1.154V   7.538mA    7.14mA     6.787mA
-949mV    18.09mA    14.34mA    17.47mA
-826mV    19.22mA    17.51mA    17.17mA
-580mV    16.24mA    15.26mA    14.54mA
937mV     -27.93mA   -26.08mA   -26.45mA
1.839V    -47.32mA   -44.03mA   -45.05mA
2.208V    -46.74mA   -42.69mA   -43.62mA
2.331V    -44.67mA   -34.74mA   -43.14mA
2.413V    -37.28mA   -26.36mA   -41.53mA
2.536V    -21.82mA   -17.98mA   -26.29mA
2.7V      -13.83mA   -13.14mA   -13.25mA
[GND_clamp]
|Voltage   I(typ)   I(min)   I(max)
-1.35V    -225.5mA   -236.8mA   -221.1mA
-1.07V    -58.41mA   -70.65mA   -56.85mA
-1.042V   -49.59mA   -59.67mA   -50.43mA
-1.014V   -42.81mA   -50.34mA   -45.7mA
-986mV    -37.69mA   -42.66mA   -41.93mA
-930mV    -30.47mA   -31.63mA   -35.59mA
-846mV    -22.52mA   -21.77mA   -26.96mA
-734mV    -13.45mA   -13.14mA   -16.29mA
-622mV    -6.019mA   -6.567mA   -7.264mA
-482mV    -782.7uA   -1.472mA   -781.2uA
-314mV    -4.342uA   -42.56uA   -1.145uA
1.35V     0A         0A         0A
[POWER_clamp]
|Voltage   I(typ)   I(min)   I(max)
-1.338V   248.4mA    267.8mA    238.2mA
-1.086V   72.51mA    96.3mA     59.73mA
-1.058V   57.87mA    80.82mA    46.5mA
-1.03V    45.22mA    66.59mA    36.14mA
-1.002V   34.89mA    53.83mA    28.81mA
-946mV    21.36mA    33.5mA     20.89mA
-918mV    17.49mA    26.1mA     18.65mA
-862mV    12.87mA    16.19mA    15.32mA
-778mV    9.039mA    9.085mA    11.51mA
-610mV    4.102mA    3.705mA    5.539mA
-330mV    85.2uA     208uA      91.66uA
1.35V     0A         0A         0A
[Ramp]
| variable   typ   min   max
dV/dt_r   0.492/0.165n   0.464/0.224n   0.493/0.132n
dV/dt_f   0.500/0.111n   0.476/0.149n   0.497/93.888p
R_load = 50.000
[Rising Waveform]
R_fixture= 50.000
V_fixture= 0.0
V_fixture_min= 0.0
V_fixture_max= 0.0
|time   V(typ)   V(min)   V(max)
0s        1.092uV    6.154uV    504.8nV
404ps     -437.7uV   71.29uV    11.82mV
456ps     -2.588mV   -70.72uV   110.9mV
531ps     17.25mV    -1.806mV   412.6mV
648ps     311.5mV    15.73mV    731.7mV
749ps     616.6mV    178.6mV    795.9mV
857ps     754.9mV    440.4mV    813.4mV
1.055ns   807.1mV    695.2mV    820.3mV
1.443ns   818.4mV    763.7mV    821.7mV
10ns      819.5mV    773.1mV    821.8mV
[Rising Waveform]
R_fixture= 50.000
V_fixture= 0.675
V_fixture_min= 0.656
V_fixture_max= 0.696
|time   V(typ)   V(min)   V(max)
0s        257.6mV    258.3mV    280.7mV
406ps     257.1mV    258.4mV    290.4mV
452ps     256.6mV    258.2mV    409.5mV
524ps     276.3mV    257.8mV    750mV
619ps     556.1mV    273.7mV    1.026V
714ps     903.8mV    447.9mV    1.086V
800ps     1.027V     699.7mV    1.1V
959ps     1.075V     965.2mV    1.106V
1.315ns   1.086V     1.036V     1.107V
10ns      1.087V     1.044V     1.107V
[Falling Waveform]
R_fixture= 50.000
V_fixture= 0.675
V_fixture_min= 0.656
V_fixture_max= 0.696
|time   V(typ)   V(min)   V(max)
0s        1.087V     1.044V     1.107V
392ps     1.087V     1.044V     1.104V
432ps     1.09V      1.044V     983mV
508ps     1.077V     1.047V     521.6mV
559ps     937.7mV    1.048V     371.4mV
635ps     516.2mV    988.7mV    306.8mV
734ps     307.8mV    636.7mV    286.8mV
855ps     268.9mV    331.6mV    282mV
1.151ns   258.6mV    263.9mV    280.8mV
10ns      257.6mV    258.3mV    280.7mV
[Falling Waveform]
R_fixture= 50.000
V_fixture= 0.0
V_fixture_min= 0.0
V_fixture_max= 0.0
|time   V(typ)   V(min)   V(max)
0s        819.5mV    773.1mV    821.8mV
389ps     820.9mV    773.3mV    818.7mV
425ps     822.9mV    773.8mV    711.6mV
496ps     812.4mV    776.5mV    262.2mV
542ps     690.3mV    776.6mV    103.1mV
619ps     239.6mV    718mV      25.78mV
716ps     38.9mV     333.2mV    5.226mV
825ps     7.634mV    57.07mV    892.7uV
1.045ns   443.1uV    3.417mV    -29.69uV
10ns      1.093uV    6.142uV    511.3nV
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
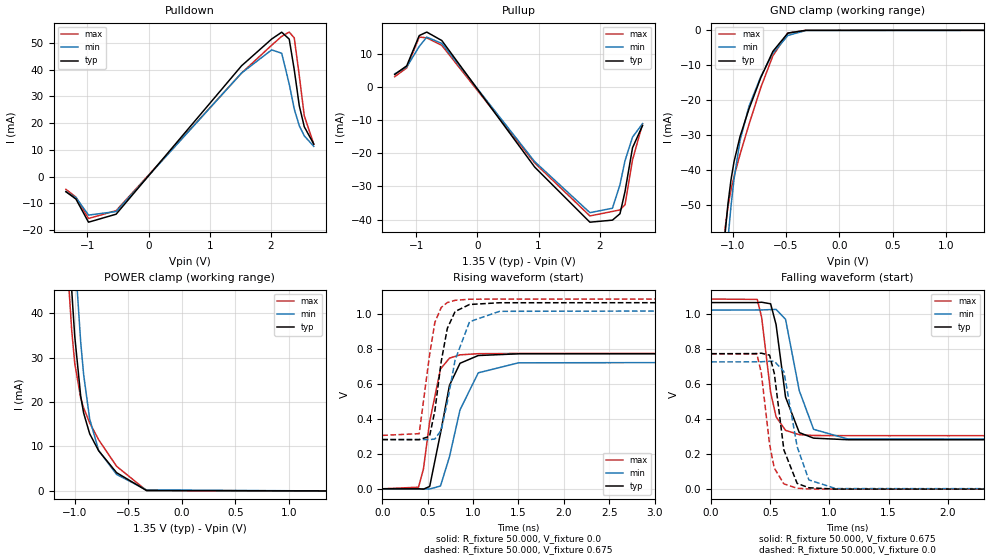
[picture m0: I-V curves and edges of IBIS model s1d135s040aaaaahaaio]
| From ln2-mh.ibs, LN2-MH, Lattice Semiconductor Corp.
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|   Model s1d135s040aaaaahaaio
[Model] s1d135s040aaaaahaaio
| Clamp models do not include dynamic input termination. Please refer to
| the s1d135axxxaaaaahaain model for input termination.
Model_type I/O
Polarity   Non-Inverting
Enable   Active-Low
Vinl =  0.575V
Vinh =  0.775V
Vmeas =  0.675V
Cref =  30.000pF
Rref =  50.000
Vref =  0.675V
C_comp   2.000pF   1.500pF   2.500pF
[Temperature Range]   25.000   0.125k   -40.000
[Voltage Range]   1.350V   1.310V   1.390V
[C Comp Corner]
C_comp   2.000pF   1.500pF   2.500pF
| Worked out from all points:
|   slope of the pulldown table from 0 to 0.203 V, typ, clamps not added: 35.6 ohm
|   slope of the pullup table from 0 to 0.203 V, typ, clamps not added: 36.9 ohm
|   GND clamp passes 1 mA (typ) near -0.49 V on its own axis
|   POWER clamp passes 1 mA (typ) near -0.45 V on its own axis
|   rising waveform, R_fixture 50.000, V_fixture 0.0: 20-80 % time 163ps typ, 218ps min, 133ps max; typ from 0 V to 0.771 V
|   rising waveform, R_fixture 50.000, V_fixture 0.675: 20-80 % time 135ps typ, 181ps min, 112ps max; typ from 0.281 V to 1.06 V
|   falling waveform, R_fixture 50.000, V_fixture 0.675: 20-80 % time 99.5ps typ, 129ps min, 90.8ps max; typ from 1.06 V to 0.281 V
|   falling waveform, R_fixture 50.000, V_fixture 0.0: 20-80 % time 92.3ps typ, 116ps min, 88.4ps max; typ from 0.771 V to 0 V
[Pulldown]
|Voltage   I(typ)   I(min)   I(max)
-1.35V    -5.632mA   -5.674mA   -4.767mA
-1.186V   -8.406mA   -7.822mA   -7.672mA
-981mV    -17.04mA   -14.39mA   -15.66mA
-530mV    -14.05mA   -13.06mA   -12.73mA
1.52V     41.41mA    38.71mA    38.69mA
2.012V    51.41mA    47.36mA    49.11mA
2.176V    53.96mA    46.1mA     52.41mA
2.299V    51.38mA    34.57mA    54.01mA
2.381V    39.95mA    25.26mA    51.84mA
2.463V    26.52mA    19.01mA    37.82mA
2.545V    18.62mA    15.22mA    22.73mA
2.7V      12.16mA    11.31mA    12.13mA
[Pullup]
|Voltage   I(typ)   I(min)   I(max)
-1.35V    3.793mA    3.989mA    3.114mA
-1.154V   6.389mA    6.04mA     5.775mA
-949mV    15.54mA    12.26mA    15.08mA
-826mV    16.58mA    15.06mA    14.84mA
-580mV    14.02mA    13.16mA    12.57mA
937mV     -24.15mA   -22.51mA   -22.91mA
1.839V    -40.79mA   -37.91mA   -38.9mA
2.208V    -40.17mA   -36.58mA   -37.54mA
2.331V    -38.24mA   -29.47mA   -37.08mA
2.413V    -31.55mA   -22.24mA   -35.53mA
2.536V    -18.32mA   -15.13mA   -21.98mA
2.7V      -11.62mA   -11.04mA   -11.11mA
[GND_clamp]
|Voltage   I(typ)   I(min)   I(max)
-1.35V    -225.5mA   -236.8mA   -221.1mA
-1.07V    -58.4mA    -70.65mA   -56.85mA
-1.042V   -49.58mA   -59.67mA   -50.43mA
-1.014V   -42.81mA   -50.34mA   -45.7mA
-986mV    -37.69mA   -42.66mA   -41.93mA
-930mV    -30.47mA   -31.63mA   -35.58mA
-846mV    -22.52mA   -21.77mA   -26.96mA
-734mV    -13.45mA   -13.14mA   -16.28mA
-622mV    -6.019mA   -6.567mA   -7.264mA
-482mV    -782.7uA   -1.472mA   -781.2uA
-314mV    -4.342uA   -42.56uA   -1.145uA
1.35V     0A         0A         0A
[POWER_clamp]
|Voltage   I(typ)   I(min)   I(max)
-1.338V   248.4mA    267.8mA    238.2mA
-1.086V   72.51mA    96.3mA     59.73mA
-1.058V   57.87mA    80.82mA    46.5mA
-1.03V    45.22mA    66.59mA    36.14mA
-1.002V   34.89mA    53.83mA    28.81mA
-946mV    21.36mA    33.5mA     20.89mA
-918mV    17.49mA    26.1mA     18.65mA
-862mV    12.87mA    16.19mA    15.32mA
-778mV    9.039mA    9.085mA    11.51mA
-610mV    4.102mA    3.705mA    5.539mA
-330mV    85.2uA     208uA      91.66uA
1.35V     0A         0A         0A
[Ramp]
| variable   typ   min   max
dV/dt_r   0.463/0.163n   0.435/0.219n   0.464/0.133n
dV/dt_f   0.472/0.113n   0.448/0.153n   0.469/96.421p
R_load = 50.000
[Rising Waveform]
R_fixture= 50.000
V_fixture= 0.0
V_fixture_min= 0.0
V_fixture_max= 0.0
|time   V(typ)   V(min)   V(max)
0s        1.215uV    6.808uV    559nV
399ps     -293.6uV   68.34uV    9.014mV
453ps     -2.183mV   -33.89uV   113mV
522ps     13.4mV     -1.279mV   383.9mV
641ps     317.4mV    15.81mV    683.8mV
740ps     590.5mV    182.9mV    745.7mV
856ps     716.4mV    450.3mV    764.6mV
1.057ns   760.7mV    662mV      771.2mV
1.502ns   770.5mV    719.1mV    772.4mV
10ns      771.2mV    725.1mV    772.5mV
[Rising Waveform]
R_fixture= 50.000
V_fixture= 0.675
V_fixture_min= 0.656
V_fixture_max= 0.696
|time   V(typ)   V(min)   V(max)
0s        280.9mV    281.2mV    304.7mV
406ps     280.4mV    281.3mV    314.7mV
520ps     299.1mV    280.8mV    761.6mV
579ps     445.5mV    284mV      950.1mV
649ps     726.6mV    335.1mV    1.035V
716ps     915.2mV    493.7mV    1.063V
802ps     1.012V     735.2mV    1.076V
961ps     1.052V     953.7mV    1.082V
1.291ns   1.062V     1.013V     1.083V
10ns      1.063V     1.021V     1.083V
[Falling Waveform]
R_fixture= 50.000
V_fixture= 0.675
V_fixture_min= 0.656
V_fixture_max= 0.696
|time   V(typ)   V(min)   V(max)
0s        1.063V     1.02V      1.083V
390ps     1.063V     1.021V     1.081V
427ps     1.065V     1.021V     978.9mV
503ps     1.056V     1.023V     551.2mV
549ps     937.1mV    1.024V     412.2mV
629ps     524.4mV    967.7mV    335mV
745ps     322.3mV    561.1mV    310.4mV
866ps     290.6mV    340.9mV    305.8mV
1.152ns   281.6mV    286.3mV    304.7mV
10ns      280.9mV    281.2mV    304.7mV
[Falling Waveform]
R_fixture= 50.000
V_fixture= 0.0
V_fixture_min= 0.0
V_fixture_max= 0.0
|time   V(typ)   V(min)   V(max)
0s        771.2mV    725.1mV    772.5mV
387ps     772.6mV    725.3mV    770.3mV
424ps     774.6mV    725.9mV    662mV
494ps     763.5mV    728.6mV    255.5mV
534ps     659.7mV    728.7mV    119.7mV
615ps     223.4mV    670.1mV    30.04mV
727ps     32.75mV    242.3mV    5.17mV
826ps     7.997mV    52.84mV    1.093mV
1.053ns   387.8uV    3.275mV    -52.69uV
10ns      1.217uV    6.798uV    567nV
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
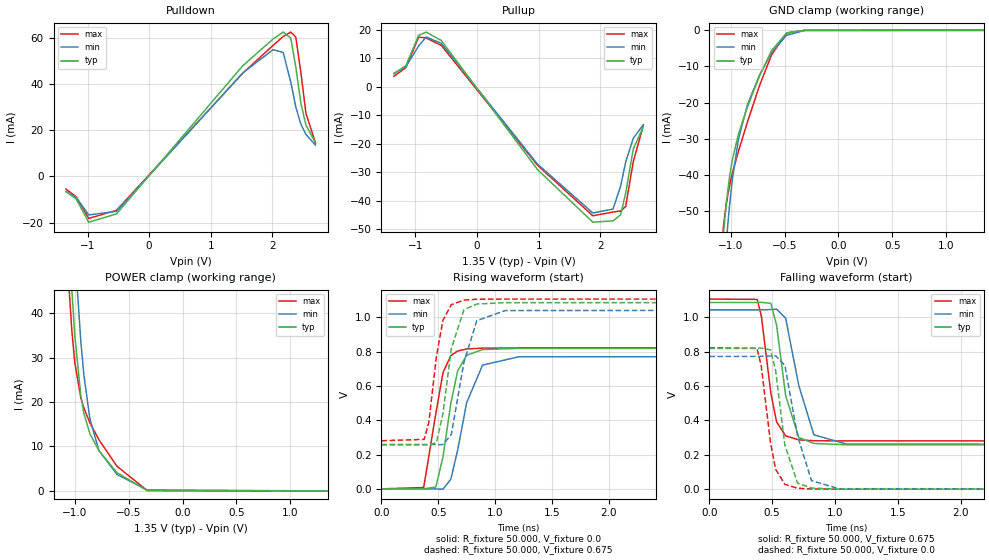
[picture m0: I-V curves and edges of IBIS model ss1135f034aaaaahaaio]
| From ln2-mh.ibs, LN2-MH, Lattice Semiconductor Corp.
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|   Model ss1135f034aaaaahaaio
[Model] ss1135f034aaaaahaaio
| Clamp models do not include dynamic input termination. Please refer to
| the ss1135axxxaaaaahaain model for input termination.
Model_type I/O
Polarity   Non-Inverting
Enable   Active-Low
Vinl =  0.575V
Vinh =  0.775V
Vmeas =  0.675V
Cref =  30.000pF
Rref =  50.000
Vref =  0.675V
C_comp   2.000pF   1.500pF   2.500pF
[Temperature Range]   25.000   0.125k   -40.000
[Voltage Range]   1.350V   1.310V   1.390V
[C Comp Corner]
C_comp   2.000pF   1.500pF   2.500pF
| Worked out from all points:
|   slope of the pulldown table from 0 to 0.203 V, typ, clamps not added: 30.8 ohm
|   slope of the pullup table from 0 to 0.203 V, typ, clamps not added: 31.9 ohm
|   GND clamp passes 1 mA (typ) near -0.50 V on its own axis
|   POWER clamp passes 1 mA (typ) near -0.45 V on its own axis
|   rising waveform, R_fixture 50.000, V_fixture 0.0: 20-80 % time 120ps typ, 146ps min, 107ps max; typ from 0 V to 0.82 V
|   rising waveform, R_fixture 50.000, V_fixture 0.675: 20-80 % time 106ps typ, 126ps min, 97.6ps max; typ from 0.258 V to 1.09 V
|   falling waveform, R_fixture 50.000, V_fixture 0.675: 20-80 % time 94.8ps typ, 123ps min, 89.7ps max; typ from 1.09 V to 0.258 V
|   falling waveform, R_fixture 50.000, V_fixture 0.0: 20-80 % time 90.3ps typ, 114ps min, 87.4ps max; typ from 0.82 V to 0 V
[Pulldown]
|Voltage   I(typ)   I(min)   I(max)
-1.35V    -6.595mA   -6.653mA   -5.549mA
-1.186V   -9.782mA   -9.127mA   -8.847mA
-981mV    -19.86mA   -16.75mA   -18.23mA
-530mV    -16.27mA   -15.14mA   -14.72mA
1.52V     47.81mA    44.72mA    44.59mA
2.012V    59.39mA    54.77mA    56.64mA
2.176V    62.38mA    53.59mA    60.45mA
2.299V    59.81mA    40.78mA    62.37mA
2.381V    47.31mA    29.97mA    60.23mA
2.463V    31.69mA    22.6mA     45.04mA
2.545V    22.23mA    18.12mA    27.31mA
2.7V      14.5mA     13.51mA    14.43mA
[Pullup]
|Voltage   I(typ)   I(min)   I(max)
-1.35V    4.507mA    4.756mA    3.675mA
-1.154V   7.531mA    7.137mA    6.77mA
-949mV    18.07mA    14.33mA    17.43mA
-826mV    19.22mA    17.5mA     17.16mA
-580mV    16.24mA    15.26mA    14.54mA
978mV     -29.01mA   -27.09mA   -27.49mA
1.88V     -47.56mA   -44.32mA   -45.3mA
2.208V    -47.08mA   -42.95mA   -43.99mA
2.331V    -44.99mA   -34.85mA   -43.61mA
2.413V    -37.35mA   -26.43mA   -42.01mA
2.536V    -21.88mA   -18.1mA    -26.36mA
2.7V      -13.99mA   -13.31mA   -13.52mA
[GND_clamp]
|Voltage   I(typ)   I(min)   I(max)
-1.35V    -224.6mA   -236.1mA   -220mA
-1.07V    -56.72mA   -69.44mA   -54.48mA
-1.042V   -47.78mA   -58.39mA   -47.95mA
-1.014V   -40.95mA   -48.99mA   -43.23mA
-986mV    -35.83mA   -41.27mA   -39.56mA
-930mV    -28.77mA   -30.24mA   -33.52mA
-846mV    -21.21mA   -20.61mA   -25.4mA
-734mV    -12.66mA   -12.39mA   -15.33mA
-622mV    -5.646mA   -6.175mA   -6.812mA
-482mV    -724.7uA   -1.376mA   -718.8uA
-314mV    -4.112uA   -39.82uA   -1.108uA
1.35V     0A         0A         0A
[POWER_clamp]
|Voltage   I(typ)   I(min)   I(max)
-1.338V   248.4mA    267.8mA    238.2mA
-1.086V   72.51mA    96.3mA     59.72mA
-1.058V   57.87mA    80.81mA    46.49mA
-1.03V    45.21mA    66.58mA    36.13mA
-1.002V   34.88mA    53.83mA    28.8mA
-946mV    21.35mA    33.5mA     20.88mA
-918mV    17.48mA    26.1mA     18.64mA
-862mV    12.87mA    16.19mA    15.31mA
-778mV    9.037mA    9.084mA    11.51mA
-610mV    4.102mA    3.705mA    5.539mA
-330mV    85.19uA    208uA      91.66uA
1.35V     0A         0A         0A
[Ramp]
| variable   typ   min   max
dV/dt_r   0.492/0.120n   0.464/0.146n   0.493/0.108n
dV/dt_f   0.500/0.104n   0.476/0.138n   0.497/93.617p
R_load = 50.000
[Rising Waveform]
R_fixture= 50.000
V_fixture= 0.0
V_fixture_min= 0.0
V_fixture_max= 0.0
|time   V(typ)   V(min)   V(max)
0s        1.092uV    6.154uV    504.8nV
371ps     57.77uV    44.2uV     7.619mV
478ps     10.88mV    -404.2uV   438.2mV
541ps     185.2mV    -1.796mV   678.2mV
610ps     499.9mV    56mV       776.9mV
670ps     688.5mV    226mV      803.9mV
749ps     779.2mV    502.6mV    815.9mV
889ps     812.5mV    722mV      820.8mV
1.206ns   819.2mV    770.1mV    821.8mV
10ns      819.5mV    773.1mV    821.8mV
[Rising Waveform]
R_fixture= 50.000
V_fixture= 0.675
V_fixture_min= 0.656
V_fixture_max= 0.696
|time   V(typ)   V(min)   V(max)
0s        257.6mV    258.3mV    280.7mV
376ps     257.6mV    258.4mV    288.6mV
417ps     257.1mV    258.4mV    390.5mV
483ps     269.2mV    257.9mV    770.5mV
540ps     436.7mV    258mV      982.6mV
614ps     817.7mV    316.5mV    1.074V
725ps     1.045V     737.8mV    1.101V
838ps     1.078V     981.1mV    1.106V
1.089ns   1.086V     1.04V      1.107V
10ns      1.087V     1.044V     1.107V
[Falling Waveform]
R_fixture= 50.000
V_fixture= 0.675
V_fixture_min= 0.656
V_fixture_max= 0.696
|time   V(typ)   V(min)   V(max)
0s        1.087V     1.044V     1.107V
381ps     1.087V     1.044V     1.105V
414ps     1.088V     1.044V     1.007V
489ps     1.082V     1.046V     561.4mV
535ps     955.2mV    1.048V     392.1mV
607ps     546.2mV    996.1mV    310.6mV
712ps     300.7mV    602.8mV    286.8mV
832ps     266.1mV    316.4mV    282.2mV
1.092ns   258.5mV    262.6mV    280.9mV
10ns      257.6mV    258.3mV    280.7mV
[Falling Waveform]
R_fixture= 50.000
V_fixture= 0.0
V_fixture_min= 0.0
V_fixture_max= 0.0
|time   V(typ)   V(min)   V(max)
0s        819.5mV    773.1mV    821.8mV
379ps     820mV      773.2mV    820.2mV
413ps     821.8mV    773.4mV    717.7mV
487ps     811mV      775.5mV    269mV
528ps     687.8mV    776.5mV    114.9mV
601ps     257.1mV    720.5mV    27.93mV
702ps     35.51mV    309.6mV    5.426mV
813ps     6.409mV    49.67mV    1.226mV
1.029ns   648.8uV    2.816mV    158uV
10ns      1.076uV    6.129uV    490.4nV
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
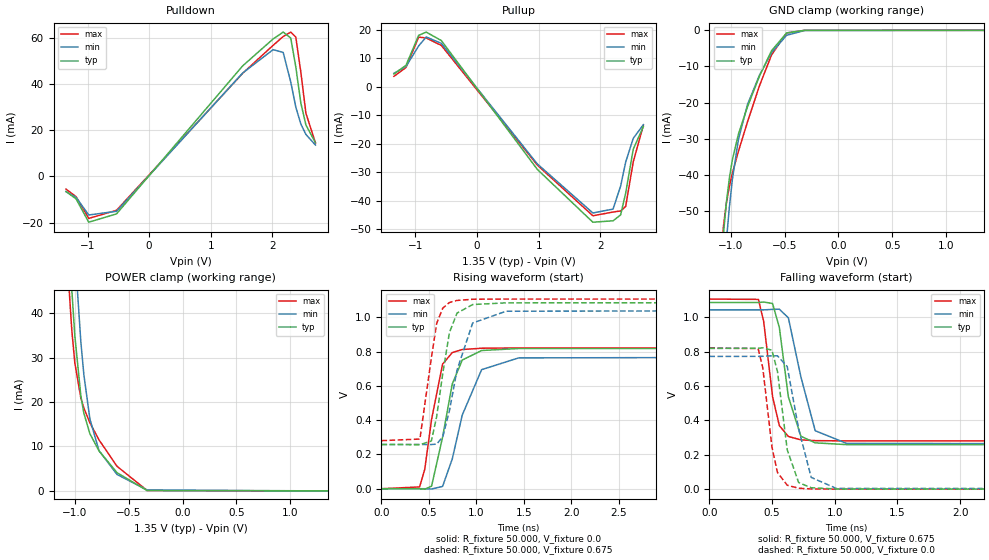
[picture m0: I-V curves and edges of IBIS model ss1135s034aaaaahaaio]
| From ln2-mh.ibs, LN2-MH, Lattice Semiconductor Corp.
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|   Model ss1135s034aaaaahaaio
[Model] ss1135s034aaaaahaaio
| Clamp models do not include dynamic input termination. Please refer to
| the ss1135axxxaaaaahaain model for input termination.
Model_type I/O
Polarity   Non-Inverting
Enable   Active-Low
Vinl =  0.575V
Vinh =  0.775V
Vmeas =  0.675V
Cref =  30.000pF
Rref =  50.000
Vref =  0.675V
C_comp   2.000pF   1.500pF   2.500pF
[Temperature Range]   25.000   0.125k   -40.000
[Voltage Range]   1.350V   1.310V   1.390V
[C Comp Corner]
C_comp   2.000pF   1.500pF   2.500pF
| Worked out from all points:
|   slope of the pulldown table from 0 to 0.203 V, typ, clamps not added: 30.8 ohm
|   slope of the pullup table from 0 to 0.203 V, typ, clamps not added: 31.9 ohm
|   GND clamp passes 1 mA (typ) near -0.50 V on its own axis
|   POWER clamp passes 1 mA (typ) near -0.45 V on its own axis
|   rising waveform, R_fixture 50.000, V_fixture 0.0: 20-80 % time 166ps typ, 224ps min, 132ps max; typ from 0 V to 0.82 V
|   rising waveform, R_fixture 50.000, V_fixture 0.675: 20-80 % time 138ps typ, 184ps min, 112ps max; typ from 0.258 V to 1.09 V
|   falling waveform, R_fixture 50.000, V_fixture 0.675: 20-80 % time 96.6ps typ, 125ps min, 86.6ps max; typ from 1.09 V to 0.258 V
|   falling waveform, R_fixture 50.000, V_fixture 0.0: 20-80 % time 88.9ps typ, 112ps min, 83.6ps max; typ from 0.82 V to 0 V
[Pulldown]
|Voltage   I(typ)   I(min)   I(max)
-1.35V    -6.595mA   -6.653mA   -5.549mA
-1.186V   -9.782mA   -9.127mA   -8.847mA
-981mV    -19.86mA   -16.75mA   -18.23mA
-530mV    -16.27mA   -15.14mA   -14.72mA
1.52V     47.81mA    44.72mA    44.59mA
2.012V    59.39mA    54.77mA    56.64mA
2.176V    62.38mA    53.59mA    60.45mA
2.299V    59.81mA    40.78mA    62.37mA
2.381V    47.31mA    29.97mA    60.23mA
2.463V    31.69mA    22.6mA     45.04mA
2.545V    22.23mA    18.12mA    27.31mA
2.7V      14.5mA     13.51mA    14.43mA
[Pullup]
|Voltage   I(typ)   I(min)   I(max)
-1.35V    4.507mA    4.756mA    3.675mA
-1.154V   7.531mA    7.137mA    6.77mA
-949mV    18.07mA    14.33mA    17.43mA
-826mV    19.22mA    17.5mA     17.16mA
-580mV    16.24mA    15.26mA    14.54mA
978mV     -29.01mA   -27.09mA   -27.49mA
1.88V     -47.56mA   -44.32mA   -45.3mA
2.208V    -47.08mA   -42.95mA   -43.99mA
2.331V    -44.99mA   -34.85mA   -43.61mA
2.413V    -37.35mA   -26.43mA   -42.01mA
2.536V    -21.88mA   -18.1mA    -26.36mA
2.7V      -13.99mA   -13.31mA   -13.52mA
[GND_clamp]
|Voltage   I(typ)   I(min)   I(max)
-1.35V    -224.6mA   -236.1mA   -220mA
-1.07V    -56.72mA   -69.44mA   -54.48mA
-1.042V   -47.78mA   -58.39mA   -47.95mA
-1.014V   -40.95mA   -48.99mA   -43.23mA
-986mV    -35.83mA   -41.27mA   -39.56mA
-930mV    -28.77mA   -30.24mA   -33.52mA
-846mV    -21.21mA   -20.61mA   -25.4mA
-734mV    -12.66mA   -12.39mA   -15.33mA
-622mV    -5.646mA   -6.175mA   -6.812mA
-482mV    -724.7uA   -1.376mA   -718.8uA
-314mV    -4.112uA   -39.82uA   -1.108uA
1.35V     0A         0A         0A
[POWER_clamp]
|Voltage   I(typ)   I(min)   I(max)
-1.338V   248.4mA    267.8mA    238.2mA
-1.086V   72.51mA    96.3mA     59.72mA
-1.058V   57.87mA    80.81mA    46.49mA
-1.03V    45.21mA    66.58mA    36.13mA
-1.002V   34.88mA    53.83mA    28.8mA
-946mV    21.35mA    33.5mA     20.88mA
-918mV    17.48mA    26.1mA     18.64mA
-862mV    12.87mA    16.19mA    15.31mA
-778mV    9.037mA    9.084mA    11.51mA
-610mV    4.102mA    3.705mA    5.539mA
-330mV    85.19uA    208uA      91.66uA
1.35V     0A         0A         0A
[Ramp]
| variable   typ   min   max
dV/dt_r   0.492/0.166n   0.464/0.224n   0.493/0.133n
dV/dt_f   0.500/0.110n   0.476/0.147n   0.497/93.078p
R_load = 50.000
[Rising Waveform]
R_fixture= 50.000
V_fixture= 0.0
V_fixture_min= 0.0
V_fixture_max= 0.0
|time   V(typ)   V(min)   V(max)
0s        1.092uV    6.154uV    504.8nV
402ps     -393.9uV   69.63uV    10.4mV
456ps     -2.622mV   -70.87uV   113.1mV
528ps     14.88mV    -1.677mV   403.8mV
644ps     301mV      13.39mV    727.4mV
746ps     611.5mV    174mV      794.8mV
851ps     750.9mV    429.8mV    812.5mV
1.055ns   806.7mV    694.9mV    820.1mV
1.445ns   818.3mV    763.6mV    821.7mV
10ns      819.5mV    773.1mV    821.8mV
[Rising Waveform]
R_fixture= 50.000
V_fixture= 0.675
V_fixture_min= 0.656
V_fixture_max= 0.696
|time   V(typ)   V(min)   V(max)
0s        257.6mV    258.3mV    280.7mV
405ps     257.1mV    258.4mV    289.8mV
526ps     278.7mV    257.8mV    764.4mV
582ps     421.6mV    260.6mV    965.2mV
646ps     673.4mV    302.6mV    1.054V
716ps     911.4mV    455.1mV    1.087V
796ps     1.025V     692.3mV    1.099V
961ps     1.075V     967.3mV    1.106V
1.313ns   1.085V     1.036V     1.107V
10ns      1.087V     1.044V     1.107V
[Falling Waveform]
R_fixture= 50.000
V_fixture= 0.675
V_fixture_min= 0.656
V_fixture_max= 0.696
|time   V(typ)   V(min)   V(max)
0s        1.087V     1.044V     1.107V
391ps     1.087V     1.044V     1.105V
433ps     1.09V      1.044V     977.7mV
504ps     1.081V     1.047V     538.8mV
558ps     941.9mV    1.048V     370.1mV
630ps     538.1mV    997.8mV    306.8mV
730ps     308mV      653.3mV    287.2mV
844ps     269.8mV    340.5mV    282.6mV
1.094ns   259.4mV    266.5mV    281mV
10ns      257.6mV    258.3mV    280.7mV
[Falling Waveform]
R_fixture= 50.000
V_fixture= 0.0
V_fixture_min= 0.0
V_fixture_max= 0.0
|time   V(typ)   V(min)   V(max)
0s        819.5mV    773.1mV    821.8mV
389ps     820.9mV    773.3mV    818.7mV
426ps     823mV      773.8mV    706.3mV
499ps     809.2mV    776.6mV    245.3mV
543ps     685.5mV    776.5mV    97.45mV
621ps     229mV      713.9mV    22.79mV
712ps     38.7mV     350.8mV    5.467mV
812ps     8.288mV    68.56mV    1.497mV
1.012ns   1.056mV    4.387mV    237.5uV
10ns      1.077uV    6.13uV     491.4nV
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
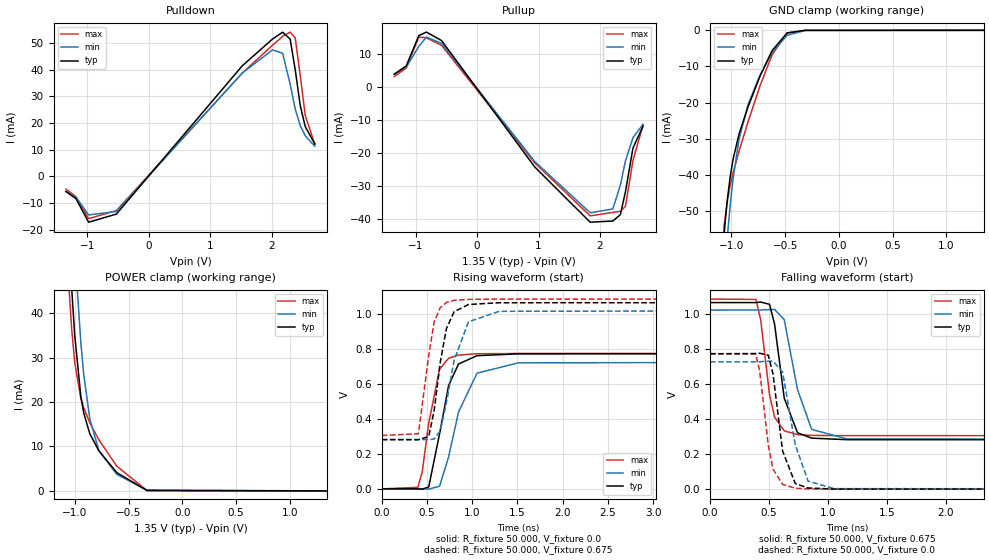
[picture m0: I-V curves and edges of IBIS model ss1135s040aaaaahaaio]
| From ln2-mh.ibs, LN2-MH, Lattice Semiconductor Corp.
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|   Model ss1135s040aaaaahaaio
[Model] ss1135s040aaaaahaaio
| Clamp models do not include dynamic input termination. Please refer to
| the ss1135axxxaaaaahaain model for input termination.
Model_type I/O
Polarity   Non-Inverting
Enable   Active-Low
Vinl =  0.575V
Vinh =  0.775V
Vmeas =  0.675V
Cref =  30.000pF
Rref =  50.000
Vref =  0.675V
C_comp   2.000pF   1.500pF   2.500pF
[Temperature Range]   25.000   0.125k   -40.000
[Voltage Range]   1.350V   1.310V   1.390V
[C Comp Corner]
C_comp   2.000pF   1.500pF   2.500pF
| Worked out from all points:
|   slope of the pulldown table from 0 to 0.203 V, typ, clamps not added: 35.6 ohm
|   slope of the pullup table from 0 to 0.203 V, typ, clamps not added: 36.9 ohm
|   GND clamp passes 1 mA (typ) near -0.50 V on its own axis
|   POWER clamp passes 1 mA (typ) near -0.45 V on its own axis
|   rising waveform, R_fixture 50.000, V_fixture 0.0: 20-80 % time 163ps typ, 219ps min, 133ps max; typ from 0 V to 0.771 V
|   rising waveform, R_fixture 50.000, V_fixture 0.675: 20-80 % time 134ps typ, 180ps min, 111ps max; typ from 0.281 V to 1.06 V
|   falling waveform, R_fixture 50.000, V_fixture 0.675: 20-80 % time 98.8ps typ, 128ps min, 89.9ps max; typ from 1.06 V to 0.281 V
|   falling waveform, R_fixture 50.000, V_fixture 0.0: 20-80 % time 91.5ps typ, 115ps min, 87.5ps max; typ from 0.771 V to 0 V
[Pulldown]
|Voltage   I(typ)   I(min)   I(max)
-1.35V    -5.611mA   -5.657mA   -4.743mA
-1.186V   -8.338mA   -7.786mA   -7.567mA
-981mV    -17.1mA    -14.39mA   -15.77mA
-530mV    -14.07mA   -13.09mA   -12.76mA
1.52V     41.41mA    38.71mA    38.69mA
2.012V    51.41mA    47.36mA    49.11mA
2.176V    53.96mA    46.1mA     52.41mA
2.299V    51.38mA    34.57mA    54.01mA
2.381V    39.95mA    25.26mA    51.84mA
2.463V    26.51mA    19.01mA    37.82mA
2.545V    18.62mA    15.22mA    22.77mA
2.7V      12.16mA    11.31mA    12.13mA
[Pullup]
|Voltage   I(typ)   I(min)   I(max)
-1.35V    3.79mA     3.988mA    3.105mA
-1.154V   6.383mA    6.037mA    5.758mA
-949mV    15.52mA    12.25mA    15.05mA
-826mV    16.57mA    15.06mA    14.83mA
-580mV    14.02mA    13.16mA    12.57mA
937mV     -24.15mA   -22.51mA   -22.91mA
1.839V    -40.83mA   -37.99mA   -38.92mA
2.208V    -40.48mA   -36.83mA   -37.88mA
2.331V    -38.55mA   -29.61mA   -37.54mA
2.413V    -31.67mA   -22.36mA   -36.05mA
2.536V    -18.44mA   -15.29mA   -22.19mA
2.7V      -11.83mA   -11.24mA   -11.45mA
[GND_clamp]
|Voltage   I(typ)   I(min)   I(max)
-1.35V    -224.6mA   -236.1mA   -220mA
-1.07V    -56.72mA   -69.44mA   -54.48mA
-1.042V   -47.78mA   -58.39mA   -47.95mA
-1.014V   -40.95mA   -48.99mA   -43.23mA
-986mV    -35.83mA   -41.27mA   -39.56mA
-930mV    -28.77mA   -30.24mA   -33.52mA
-846mV    -21.21mA   -20.61mA   -25.4mA
-734mV    -12.66mA   -12.39mA   -15.33mA
-622mV    -5.646mA   -6.175mA   -6.812mA
-482mV    -724.7uA   -1.376mA   -718.8uA
-314mV    -4.112uA   -39.82uA   -1.108uA
1.35V     0A         0A         0A
[POWER_clamp]
|Voltage   I(typ)   I(min)   I(max)
-1.338V   248.4mA    267.8mA    238.2mA
-1.086V   72.51mA    96.3mA     59.72mA
-1.058V   57.87mA    80.81mA    46.49mA
-1.03V    45.21mA    66.58mA    36.13mA
-1.002V   34.88mA    53.83mA    28.8mA
-946mV    21.35mA    33.5mA     20.88mA
-918mV    17.48mA    26.1mA     18.64mA
-862mV    12.87mA    16.19mA    15.31mA
-778mV    9.037mA    9.084mA    11.51mA
-610mV    4.102mA    3.705mA    5.539mA
-330mV    85.19uA    208uA      91.66uA
1.35V     0A         0A         0A
[Ramp]
| variable   typ   min   max
dV/dt_r   0.463/0.163n   0.435/0.219n   0.464/0.133n
dV/dt_f   0.472/0.112n   0.448/0.152n   0.469/95.452p
R_load = 50.000
[Rising Waveform]
R_fixture= 50.000
V_fixture= 0.0
V_fixture_min= 0.0
V_fixture_max= 0.0
|time   V(typ)   V(min)   V(max)
0s        1.215uV    6.808uV    559nV
398ps     -277.1uV   68uV       8.384mV
447ps     -1.814mV   17.6uV     96.36mV
519ps     10.96mV    -1.205mV   376mV
639ps     314.4mV    14.69mV    682.4mV
739ps     590.4mV    183.1mV    745.3mV
849ps     712.6mV    439mV      763.6mV
1.053ns   760mV      660.1mV    770.9mV
1.513ns   770.5mV    719.2mV    772.4mV
10ns      771.2mV    725.1mV    772.5mV
[Rising Waveform]
R_fixture= 50.000
V_fixture= 0.675
V_fixture_min= 0.656
V_fixture_max= 0.696
|time   V(typ)   V(min)   V(max)
0s        280.9mV    281.2mV    304.7mV
405ps     280.4mV    281.3mV    314.2mV
519ps     298.5mV    280.8mV    761.1mV
579ps     447.5mV    284mV      952.6mV
648ps     726.8mV    334.1mV    1.035V
714ps     913.9mV    489.9mV    1.063V
800ps     1.011V     733.9mV    1.076V
959ps     1.052V     953.4mV    1.081V
1.299ns   1.062V     1.013V     1.083V
10ns      1.063V     1.021V     1.083V
[Falling Waveform]
R_fixture= 50.000
V_fixture= 0.675
V_fixture_min= 0.656
V_fixture_max= 0.696
|time   V(typ)   V(min)   V(max)
0s        1.063V     1.02V      1.083V
390ps     1.063V     1.021V     1.081V
430ps     1.066V     1.021V     964.5mV
505ps     1.053V     1.023V     539.7mV
548ps     941mV      1.024V     410.8mV
630ps     518.5mV    965.8mV    332.5mV
743ps     321mV      566.7mV    310.6mV
863ps     290.7mV    340.6mV    306.3mV
1.162ns   281.9mV    286.3mV    304.9mV
10ns      280.9mV    281.2mV    304.7mV
[Falling Waveform]
R_fixture= 50.000
V_fixture= 0.0
V_fixture_min= 0.0
V_fixture_max= 0.0
|time   V(typ)   V(min)   V(max)
0s        771.2mV    725.1mV    772.5mV
387ps     772.6mV    725.3mV    770.3mV
421ps     774.5mV    725.8mV    676.4mV
495ps     762.5mV    728.7mV    249.2mV
535ps     655.2mV    728.7mV    114.1mV
616ps     218.1mV    668mV      27.36mV
724ps     31.68mV    251.8mV    5.334mV
833ps     6.744mV    45.14mV    1.332mV
1.054ns   757.3uV    3.06mV     170.7uV
10ns      1.199uV    6.785uV    545.3nV
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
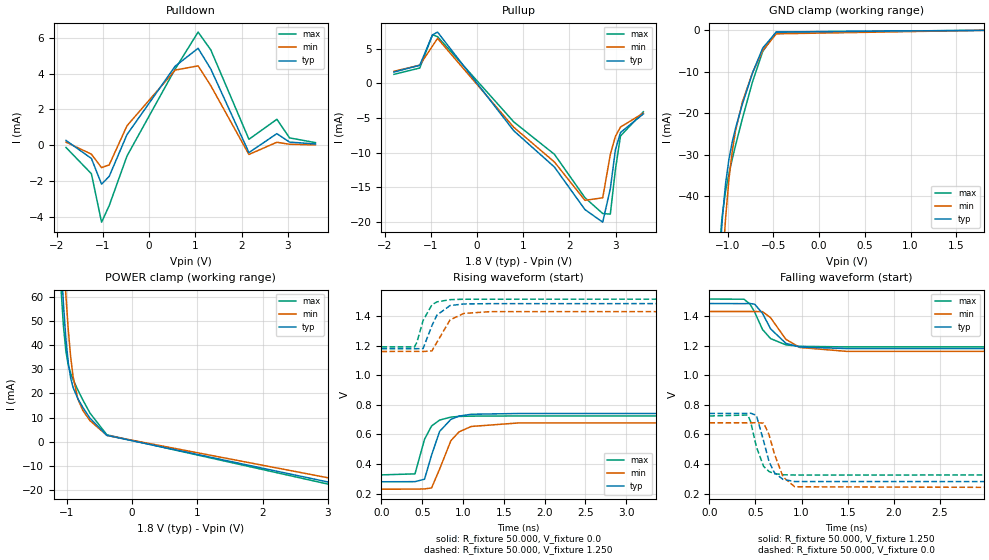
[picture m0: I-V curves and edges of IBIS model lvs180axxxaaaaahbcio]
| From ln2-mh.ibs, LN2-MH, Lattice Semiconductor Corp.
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|   Model lvs180axxxaaaaahbcio
[Model] lvs180axxxaaaaahbcio
| Clamp models do not include dynamic input termination. Please refer to
| the lvs180axxxaaaaahbain model for input termination.
Model_type I/O
Polarity   Non-Inverting
Enable   Active-Low
Vinl =  1.150V
Vinh =  1.350V
Vmeas =  1.250V
Cref =  3.000pF
Rref =  50.000
Vref =  1.250V
C_comp   2.000pF   1.500pF   2.500pF
[Temperature Range]   25.000   0.125k   -40.000
[Voltage Range]   1.800V   1.750V   1.850V
[C Comp Corner]
C_comp   2.000pF   1.500pF   2.500pF
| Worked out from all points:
|   slope of the pulldown table from 0 to 0.27 V, typ, clamps not added: 260 ohm
|   slope of the pullup table from 0 to 0.27 V, typ, clamps not added: 112 ohm
|   GND clamp passes 1 mA (typ) near -0.51 V on its own axis
|   POWER clamp passes 1 mA (typ) near -0.17 V on its own axis
|   rising waveform, R_fixture 50.000, V_fixture 0.0: 20-80 % time 172ps typ, 207ps min, 140ps max; typ from 0.281 V to 0.742 V
|   rising waveform, R_fixture 50.000, V_fixture 1.250: 20-80 % time 139ps typ, 173ps min, 125ps max; typ from 1.18 V to 1.48 V
|   falling waveform, R_fixture 50.000, V_fixture 1.250: 20-80 % time 190ps typ, 206ps min, 174ps max; typ from 1.48 V to 1.18 V
|   falling waveform, R_fixture 50.000, V_fixture 0.0: 20-80 % time 123ps typ, 141ps min, 103ps max; typ from 0.742 V to 0.281 V
[Pulldown]
|Voltage   I(typ)   I(min)   I(max)
-1.8V     271.8uA    176.4uA    -119.3uA
-1.25V    -732.6uA   -493.1uA   -1.586mA
-1.03V    -2.168mA   -1.243mA   -4.288mA
-865mV    -1.733mA   -1.094mA   -3.365mA
-480mV    596.2uA    1.089mA    -598uA
565mV     4.419mA    4.196mA    4.264mA
1.06V     5.411mA    4.432mA    6.315mA
1.335V    4.253mA    3.322mA    5.321mA
2.16V     -405.7uA   -509.8uA   335.8uA
2.765V    649.7uA    170uA      1.45mA
3.04V     179uA      57.96uA    413.5uA
3.6V      74.93uA    21.97uA    149.4uA
[Pullup]
|Voltage   I(typ)   I(min)   I(max)
-1.8V     1.648mA    1.75mA     1.318mA
-1.24V    2.632mA    2.651mA    2.231mA
-965mV    7.028mA    5.418mA    7.045mA
-855mV    7.432mA    6.519mA    6.772mA
795mV     -6.852mA   -6.352mA   -5.568mA
1.675V    -12.1mA    -11.37mA   -10.26mA
2.335V    -18.25mA   -16.92mA   -16.53mA
2.72V     -20.08mA   -16.55mA   -18.83mA
2.885V    -15.23mA   -10.27mA   -18.91mA
2.995V    -9.609mA   -7.662mA   -12.46mA
3.105V    -7.099mA   -6.308mA   -7.604mA
3.6V      -4.411mA   -4.295mA   -4.097mA
[GND_clamp]
|Voltage   I(typ)   I(min)   I(max)
-1.8V     -553.1mA   -556.1mA   -553.8mA
-1.097V   -58.47mA   -72.98mA   -54.16mA
-1.06V    -45.88mA   -57.74mA   -44.76mA
-1.023V   -37.01mA   -45.35mA   -38.78mA
-986mV    -31.04mA   -35.88mA   -34.52mA
-949mV    -26.81mA   -28.98mA   -30.92mA
-912mV    -23.45mA   -23.98mA   -27.57mA
-838mV    -17.72mA   -17.2mA    -21.19mA
-727mV    -10.2mA    -10.13mA   -12.31mA
-616mV    -4.257mA   -4.824mA   -5.069mA
-468mV    -409.6uA   -842.6uA   -395.7uA
1.8V      0A         0A         0A
[POWER_clamp]
|Voltage   I(typ)   I(min)   I(max)
-1.789V   617.9mA    625mA      616.3mA
-1.086V   75.48mA    98.36mA    63.79mA
-1.049V   57.29mA    78.52mA    48.11mA
-1.012V   42.91mA    61.08mA    37.73mA
-975mV    32.8mA     46.54mA    31.79mA
-938mV    26.42mA    35.21mA    28.27mA
-901mV    22.5mA     27.01mA    25.72mA
-827mV    17.78mA    17.65mA    21.4mA
-753mV    14.3mA     13.03mA    17.39mA
-642mV    9.75mA     8.748mA    11.87mA
-383mV    2.66mA     2.655mA    2.883mA
3.6V      -20.01mA   -17.95mA   -21.07mA
[Ramp]
| variable   typ   min   max
dV/dt_r   0.277/0.172n   0.269/0.207n   0.239/0.140n
dV/dt_f   48.057m/0.254n   36.443m/0.293n   67.175m/0.231n
R_load = 50.000
[Rising Waveform]
R_fixture= 50.000
V_fixture= 0.0
V_fixture_min= 0.0
V_fixture_max= 0.0
|time   V(typ)   V(min)   V(max)
0s        280.6mV    230.7mV    327.1mV
411ps     281.3mV    230.9mV    334mV
528ps     298.1mV    232.5mV    567.5mV
614ps     460.5mV    238.6mV    657.2mV
713ps     620.8mV    366.6mV    697mV
851ps     701.9mV    558.1mV    717.3mV
951ps     724.2mV    617.7mV    721.7mV
1.1ns     736.4mV    654mV      723.8mV
1.681ns   741.5mV    677.8mV    724.9mV
10ns      741.7mV    678.7mV    724.9mV
[Rising Waveform]
R_fixture= 50.000
V_fixture= 1.250
V_fixture_min= 1.213
V_fixture_max= 1.289
|time   V(typ)   V(min)   V(max)
0s        1.179V     1.16V      1.191V
405ps     1.179V     1.161V     1.191V
435ps     1.179V     1.161V     1.223V
510ps     1.18V      1.16V      1.369V
618ps     1.334V     1.164V     1.475V
680ps     1.406V     1.222V     1.495V
840ps     1.47V      1.373V     1.51V
1.01ns    1.481V     1.417V     1.513V
1.333ns   1.483V     1.429V     1.513V
10ns      1.484V     1.43V      1.514V
[Falling Waveform]
R_fixture= 50.000
V_fixture= 1.250
V_fixture_min= 1.213
V_fixture_max= 1.289
|time   V(typ)   V(min)   V(max)
0s        1.484V     1.43V      1.514V
376ps     1.483V     1.43V      1.513V
442ps     1.484V     1.43V      1.479V
492ps     1.479V     1.43V      1.425V
576ps     1.418V     1.429V     1.309V
664ps     1.313V     1.388V     1.247V
830ps     1.215V     1.242V     1.205V
982ps     1.19V      1.187V     1.195V
1.488ns   1.18V      1.161V     1.191V
10ns      1.179V     1.16V      1.191V
[Falling Waveform]
R_fixture= 50.000
V_fixture= 0.0
V_fixture_min= 0.0
V_fixture_max= 0.0
|time   V(typ)   V(min)   V(max)
0s        741.7mV    678.7mV    724.8mV
415ps     741.9mV    678.6mV    731.3mV
447ps     743.5mV    678.6mV    688.4mV
510ps     729.4mV    679.4mV    516.3mV
588ps     556.9mV    676.5mV    384.9mV
646ps     419.3mV    601.6mV    350.4mV
705ps     341.9mV    469.2mV    335.7mV
799ps     296.7mV    313.3mV    327.9mV
926ps     282.1mV    246.7mV    326.2mV
10ns      280.6mV    230.7mV    327.1mV
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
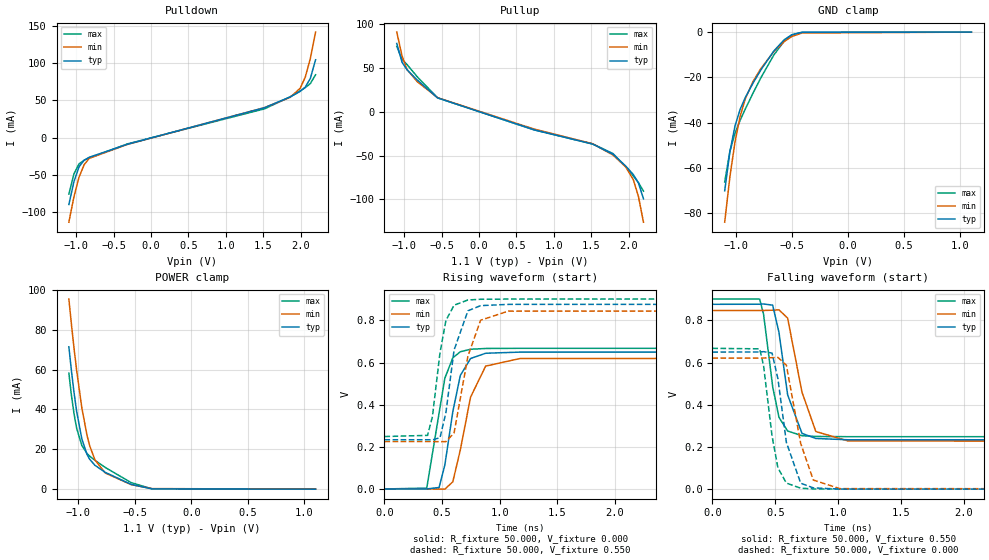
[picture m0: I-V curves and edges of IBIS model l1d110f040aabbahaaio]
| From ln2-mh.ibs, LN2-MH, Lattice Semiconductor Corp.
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|   Model l1d110f040aabbahaaio
[Model] l1d110f040aabbahaaio
| Clamp models do not include dynamic input termination. Please refer to
| the l1d110axxxaabbahaain model for input termination.
Model_type I/O
Polarity   Non-Inverting
Enable   Active-Low
Vinl =  0.200V
Vinh =  0.300V
Vmeas =  0.550V
Cref =  20.000pF
Rref =  50.000
Vref =  0.600V
C_comp   2.000pF   1.500pF   2.500pF
[Temperature Range]   25.000   0.125k   -40.000
[Voltage Range]   1.100V   1.070V   1.130V
[C Comp Corner]
C_comp   2.000pF   1.500pF   2.500pF
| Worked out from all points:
|   slope of the pulldown table from 0 to 0.165 V, typ, clamps not added: 36.9 ohm
|   slope of the pullup table from 0 to 0.165 V, typ, clamps not added: 34.3 ohm
|   GND clamp passes 1 mA (typ) near -0.49 V on its own axis
|   POWER clamp passes 1 mA (typ) near -0.45 V on its own axis
|   rising waveform, R_fixture 50.000, V_fixture 0.000: 20-80 % time 119ps typ, 144ps min, 107ps max; typ from 0 V to 0.65 V
|   rising waveform, R_fixture 50.000, V_fixture 0.550: 20-80 % time 102ps typ, 122ps min, 95.3ps max; typ from 0.233 V to 0.876 V
|   falling waveform, R_fixture 50.000, V_fixture 0.550: 20-80 % time 99.4ps typ, 123ps min, 90.8ps max; typ from 0.876 V to 0.233 V
|   falling waveform, R_fixture 50.000, V_fixture 0.000: 20-80 % time 96.2ps typ, 116ps min, 89.1ps max; typ from 0.65 V to 0 V
[Pulldown]
|Voltage   I(typ)   I(min)   I(max)
-1.1V     -89.3mA    -113mA     -75.37mA
-1.032V   -58.63mA   -78.92mA   -48.29mA
-964mV    -38.91mA   -52.76mA   -34.88mA
-896mV    -30.01mA   -36.14mA   -30.09mA
-828mV    -26.1mA    -27.54mA   -27.13mA
-318mV    -8.7mA     -8.922mA   -8.238mA
1.518V    40.3mA     40.42mA    38.8mA
1.858V    54.6mA     54.02mA    54.72mA
1.994V    62.1mA     66.32mA    62.84mA
2.062V    67.75mA    81.17mA    67.18mA
2.13V     79.49mA    106.1mA    72.58mA
2.2V      104.4mA    141.5mA    84.35mA
[Pullup]
|Voltage   I(typ)   I(min)   I(max)
-1.1V     78.01mA    91.02mA    74.66mA
-1.03V    56.62mA    63.91mA    59.8mA
-962mV    47.87mA    48.19mA    53.85mA
-826mV    36.28mA    34.36mA    39.94mA
-554mV    15.8mA     16.04mA    15.88mA
738mV     -20.65mA   -19.82mA   -20.77mA
1.52V     -36.95mA   -36.57mA   -36.79mA
1.792V    -48.46mA   -49.5mA    -47.74mA
1.962V    -62.03mA   -63.03mA   -63.03mA
2.064V    -71.8mA    -77.71mA   -73.45mA
2.132V    -81.32mA   -96.73mA   -80.93mA
2.2V      -99.48mA   -126.2mA   -90.7mA
[GND_clamp]
|Voltage   I(typ)   I(min)   I(max)
-1.1V     -70.17mA   -84.03mA   -66.28mA
-1.054V   -53mA      -64.11mA   -52.78mA
-1.008V   -41.48mA   -48.48mA   -44.68mA
-962mV    -34.13mA   -37.21mA   -38.95mA
-916mV    -28.9mA    -29.48mA   -33.97mA
-847mV    -22.51mA   -21.79mA   -26.94mA
-778mV    -16.78mA   -16.17mA   -20.25mA
-663mV    -8.429mA   -8.708mA   -10.22mA
-571mV    -3.466mA   -4.237mA   -4.093mA
-502mV    -1.18mA    -1.941mA   -1.256mA
-410mV    -105.5uA   -402.4uA   -63.37uA
1.1V      0A         0A         0A
[POWER_clamp]
|Voltage   I(typ)   I(min)   I(max)
-1.085V   71.41mA    95.35mA    58.18mA
-1.062V   59.23mA    82.55mA    46.99mA
-1.039V   48.36mA    70.56mA    37.71mA
-1.016V   38.97mA    59.53mA    30.53mA
-970mV    25.17mA    40.76mA    21.88mA
-924mV    17.37mA    26.93mA    17.87mA
-901mV    15.03mA    21.86mA    16.59mA
-855mV    12.01mA    14.79mA    14.5mA
-763mV    8.448mA    8.108mA    10.89mA
-533mV    2.369mA    2.267mA    3.272mA
-349mV    143.9uA    291.4uA    171.3uA
1.1V      0A         0A         0A
[Ramp]
| variable   typ   min   max
dV/dt_r   0.376/0.119n   0.359/0.144n   0.386/0.107n
dV/dt_f   0.379/0.106n   0.371/0.137n   0.381/93.306p
R_load = 50.000
[Rising Waveform]
R_fixture = 50.000
V_fixture = 0.000
V_fixture_min = 0.000
V_fixture_max = 0.000
|  time   V(typ)   V(min)   V(max)
0s        1.497uV    7.052uV    0V
367ps     67.98uV    48.12uV    4.108mV
474ps     7.039mV    -342.6uV   360.3mV
524ps     114mV      -959.7uV   525.7mV
593ps     366.7mV    34.07mV    622.3mV
658ps     538.4mV    184.8mV    651.1mV
747ps     619mV      435.8mV    662.9mV
878ps     644mV      583.1mV    666.6mV
1.177ns   649.4mV    619mV      667.4mV
10ns      649.7mV    621.3mV    667.5mV
[Rising Waveform]
R_fixture = 50.000
V_fixture = 0.550
V_fixture_min = 0.534
V_fixture_max = 0.568
|  time   V(typ)   V(min)   V(max)
0s        233.5mV    224.9mV    248.7mV
374ps     233.5mV    225mV      254.3mV
416ps     233.1mV    225mV      342.8mV
482ps     243.3mV    224.5mV    647.1mV
533ps     361.8mV    224.6mV    799.2mV
604ps     659.1mV    265.5mV    871.9mV
724ps     845.4mV    630mV      896.7mV
834ps     869.9mV    800.7mV    900.1mV
1.074ns   875.9mV    843.8mV    901mV
10ns      876.3mV    846.9mV    901.1mV
[Falling Waveform]
R_fixture = 50.000
V_fixture = 0.550
V_fixture_min = 0.534
V_fixture_max = 0.568
|  time   V(typ)   V(min)   V(max)
0s        876.3mV    846.9mV    901.1mV
376ps     876.6mV    846.9mV    900.9mV
407ps     877.8mV    847mV      828.7mV
479ps     872.3mV    848.4mV    486.6mV
529ps     743.5mV    850.1mV    340.6mV
598ps     447mV      810.7mV    275.7mV
712ps     264.6mV    459.9mV    253.4mV
822ps     240.3mV    273.2mV    249.9mV
1.078ns   234.1mV    228.5mV    248.8mV
10ns      233.5mV    224.9mV    248.7mV
[Falling Waveform]
R_fixture = 50.000
V_fixture = 0.000
V_fixture_min = 0.000
V_fixture_max = 0.000
|  time   V(typ)   V(min)   V(max)
0s        649.7mV    621.3mV    667.5mV
376ps     650.3mV    621.3mV    665.2mV
407ps     651.8mV    621.6mV    584.7mV
474ps     645.2mV    623.3mV    252.9mV
521ps     522.7mV    624.5mV    100.7mV
588ps     221.6mV    587.3mV    28.92mV
702ps     28.18mV    216.1mV    4.489mV
802ps     6.018mV    43.27mV    1.146mV
1.012ns   560.7uV    2.661mV    154.2uV
10ns      1.497uV    7.052uV    0V
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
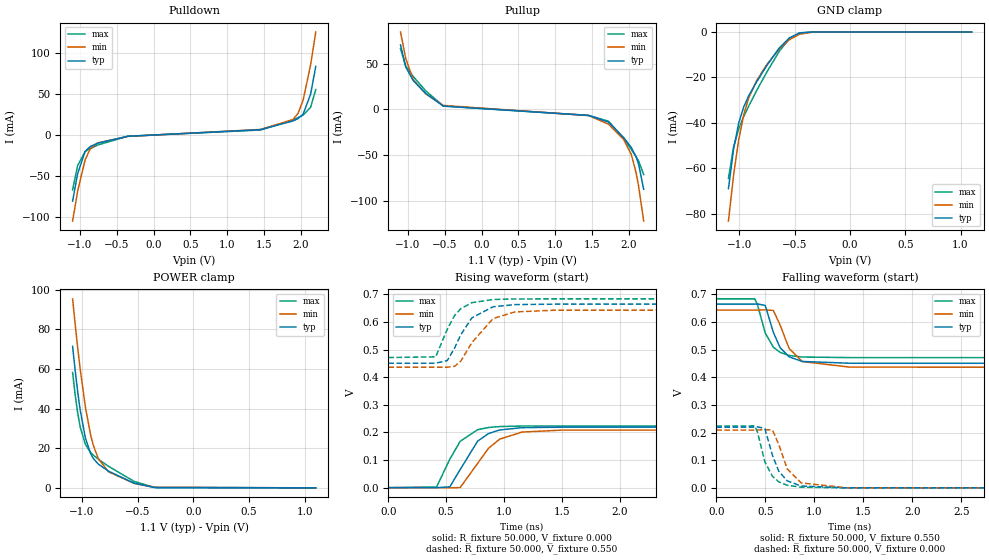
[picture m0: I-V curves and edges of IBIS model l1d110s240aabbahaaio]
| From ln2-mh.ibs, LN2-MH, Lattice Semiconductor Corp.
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|   Model l1d110s240aabbahaaio
[Model] l1d110s240aabbahaaio
| Clamp models do not include dynamic input termination. Please refer to
| the l1d110axxxaabbahaain model for input termination.
Model_type I/O
Polarity   Non-Inverting
Enable   Active-Low
Vinl =  0.200V
Vinh =  0.300V
Vmeas =  0.550V
Cref =  20.000pF
Rref =  50.000
Vref =  0.600V
C_comp   2.000pF   1.500pF   2.500pF
[Temperature Range]   25.000   0.125k   -40.000
[Voltage Range]   1.100V   1.070V   1.130V
[C Comp Corner]
C_comp   2.000pF   1.500pF   2.500pF
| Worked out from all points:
|   slope of the pulldown table from 0 to 0.165 V, typ, clamps not added: 226 ohm
|   slope of the pullup table from 0 to 0.165 V, typ, clamps not added: 189 ohm
|   GND clamp passes 1 mA (typ) near -0.49 V on its own axis
|   POWER clamp passes 1 mA (typ) near -0.45 V on its own axis
|   rising waveform, R_fixture 50.000, V_fixture 0.000: 20-80 % time 194ps typ, 223ps min, 170ps max; typ from 0 V to 0.219 V
|   rising waveform, R_fixture 50.000, V_fixture 0.550: 20-80 % time 180ps typ, 213ps min, 152ps max; typ from 0.451 V to 0.665 V
|   falling waveform, R_fixture 50.000, V_fixture 0.550: 20-80 % time 142ps typ, 158ps min, 134ps max; typ from 0.665 V to 0.451 V
|   falling waveform, R_fixture 50.000, V_fixture 0.000: 20-80 % time 136ps typ, 145ps min, 130ps max; typ from 0.219 V to 0 V
[Pulldown]
|Voltage   I(typ)   I(min)   I(max)
-1.1V     -80.78mA   -105mA     -67mA
-1.032V   -47.3mA    -68.74mA   -37.46mA
-930mV    -20.18mA   -30.3mA    -20.28mA
-862mV    -14.23mA   -17.44mA   -16.68mA
-760mV    -10.1mA    -9.799mA   -12.36mA
-352mV    -1.714mA   -1.878mA   -1.639mA
1.45V     6.351mA    6.653mA    5.969mA
1.892V    16.99mA    18.71mA    18.2mA
1.96V     19.93mA    26.39mA    21.06mA
2.028V    25.15mA    42.13mA    24.19mA
2.13V     49.57mA    85.28mA    33.6mA
2.2V      83.5mA     125.4mA    55.21mA
[Pullup]
|Voltage   I(typ)   I(min)   I(max)
-1.1V     70.77mA    84.78mA    66.46mA
-1.03V    46.58mA    55.94mA    47.71mA
-928mV    31.59mA    32.66mA    36.18mA
-758mV    17.62mA    17.06mA    20.42mA
-520mV    3.696mA    4.424mA    3.794mA
1.452V    -6.529mA   -6.64mA    -6.444mA
1.724V    -13.8mA    -16.09mA   -12.89mA
1.928V    -30.66mA   -32.78mA   -31.94mA
2.03V     -41.41mA   -48.75mA   -43.49mA
2.098V    -51.87mA   -69.53mA   -51.8mA
2.132V    -60.12mA   -84.3mA    -56.57mA
2.2V      -87.31mA   -122.1mA   -71.2mA
[GND_clamp]
|Voltage   I(typ)   I(min)   I(max)
-1.1V     -69.04mA   -83.29mA   -64.5mA
-1.054V   -51.76mA   -63.34mA   -50.8mA
-1.008V   -40.24mA   -47.71mA   -42.75mA
-962mV    -33.04mA   -36.52mA   -37.26mA
-916mV    -28.06mA   -28.96mA   -32.57mA
-847mV    -22.15mA   -21.6mA    -25.99mA
-755mV    -14.93mA   -14.48mA   -17.84mA
-640mV    -7mA       -7.443mA   -8.458mA
-548mV    -2.55mA    -3.36mA    -2.95mA
-456mV    -410.2uA   -964.6uA   -356.6uA
-341mV    -10.46uA   -82.06uA   -3.329uA
1.1V      0A         0A         0A
[POWER_clamp]
|Voltage   I(typ)   I(min)   I(max)
-1.085V   71.41mA    95.35mA    58.18mA
-1.062V   59.23mA    82.55mA    46.99mA
-1.039V   48.36mA    70.56mA    37.71mA
-1.016V   38.97mA    59.53mA    30.53mA
-970mV    25.17mA    40.76mA    21.88mA
-924mV    17.37mA    26.93mA    17.87mA
-901mV    15.03mA    21.86mA    16.59mA
-855mV    12.01mA    14.79mA    14.5mA
-763mV    8.448mA    8.108mA    10.89mA
-533mV    2.369mA    2.267mA    3.272mA
-349mV    143.9uA    291.4uA    171.3uA
1.1V      0A         0A         0A
[Ramp]
| variable   typ   min   max
dV/dt_r   0.132/0.194n   0.125/0.224n   0.134/0.171n
dV/dt_f   0.119/0.155n   0.116/0.182n   0.115/0.142n
R_load = 50.000
[Rising Waveform]
R_fixture = 50.000
V_fixture = 0.000
V_fixture_min = 0.000
V_fixture_max = 0.000
|  time   V(typ)   V(min)   V(max)
0s        2.527uV    12.65uV    1.11uV
417ps     24.09uV    252uV      2.484mV
532ps     3.001mV    -643.4uV   103.3mV
621ps     65.34mV    353.3uV    167.8mV
772ps     168.3mV    87.78mV    209.8mV
866ps     195.9mV    142.6mV    217.9mV
962ps     208.9mV    175.6mV    221.3mV
1.157ns   217.3mV    201.4mV    223.2mV
1.507ns   219.1mV    208.5mV    223.6mV
10ns      219.3mV    209.1mV    223.6mV
[Rising Waveform]
R_fixture = 50.000
V_fixture = 0.550
V_fixture_min = 0.534
V_fixture_max = 0.568
|  time   V(typ)   V(min)   V(max)
0s        450.6mV    436.2mV    471.2mV
409ps     450.7mV    436.4mV    473.7mV
510ps     460.3mV    436.2mV    573.9mV
572ps     505mV      439.4mV    623mV
626ps     553.2mV    457.7mV    648mV
722ps     614.9mV    525.2mV    669.9mV
906ps     655.1mV    612.3mV    681.4mV
1.092ns   662.9mV    636.2mV    683.3mV
1.436ns   664.6mV    642.7mV    683.7mV
10ns      664.7mV    643.2mV    683.7mV
[Falling Waveform]
R_fixture = 50.000
V_fixture = 0.550
V_fixture_min = 0.534
V_fixture_max = 0.568
|  time   V(typ)   V(min)   V(max)
0s        664.7mV    643.2mV    683.7mV
392ps     664.8mV    643.2mV    683.7mV
420ps     665.2mV    643.2mV    663.1mV
499ps     660.2mV    644mV      560.1mV
582ps     562.7mV    641.7mV    509mV
651ps     507.1mV    589.2mV    490mV
743ps     473.9mV    504mV      478.8mV
877ps     457.3mV    456.9mV    473.3mV
1.364ns   450.8mV    436.7mV    471.2mV
10ns      450.6mV    436.2mV    471.2mV
[Falling Waveform]
R_fixture = 50.000
V_fixture = 0.000
V_fixture_min = 0.000
V_fixture_max = 0.000
|  time   V(typ)   V(min)   V(max)
0s        219.3mV    209.1mV    223.6mV
391ps     219.8mV    209.1mV    224.1mV
420ps     220.5mV    209.3mV    202.2mV
495ps     214.9mV    210.8mV    94.79mV
573ps     118mV      208.9mV    41.79mV
637ps     60.44mV    157.4mV    21.79mV
723ps     25.59mV    68.87mV    9.278mV
865ps     6.619mV    17.83mV    2.384mV
1.323ns   169.1uV    442.8uV    70.39uV
10ns      2.527uV    12.65uV    1.11uV
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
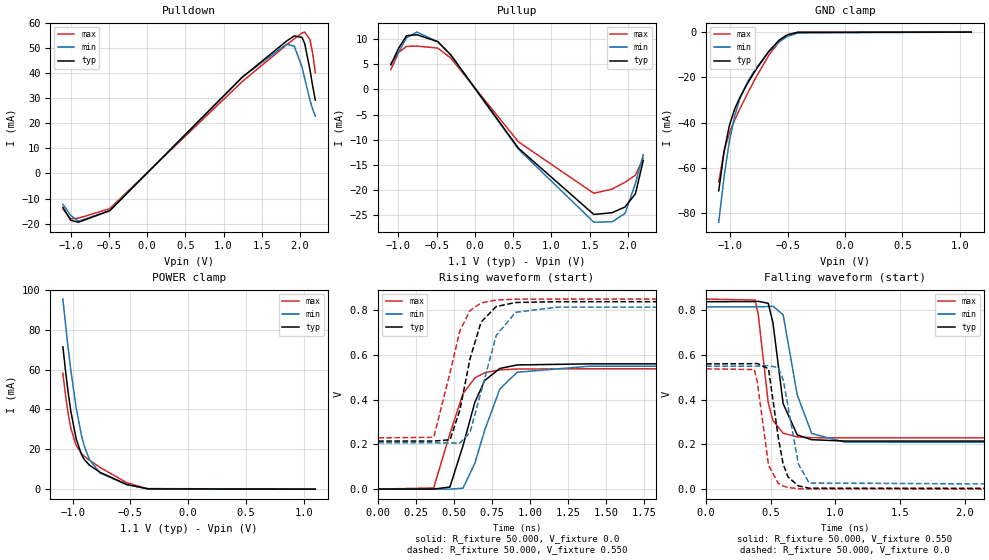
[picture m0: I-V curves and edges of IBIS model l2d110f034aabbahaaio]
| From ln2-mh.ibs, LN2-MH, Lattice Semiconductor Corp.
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|   Model l2d110f034aabbahaaio
[Model] l2d110f034aabbahaaio
| Clamp models do not include dynamic input termination. Please refer to
| the l2d110axxxaabbahaain model for input termination.
Model_type I/O
Polarity   Non-Inverting
Enable   Active-Low
Vinl =  0.200V
Vinh =  0.300V
Vmeas =  0.550V
Cref =  20.000pF
Rref =  50.000
Vref =  0.600V
C_comp   2.000pF   1.500pF   2.500pF
[Temperature Range]   25.000   0.125k   -40.000
[Voltage Range]   1.100V   1.070V   1.130V
[C Comp Corner]
C_comp   2.000pF   1.500pF   2.500pF
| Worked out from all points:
|   slope of the pulldown table from 0 to 0.165 V, typ, clamps not added: 31.9 ohm
|   slope of the pullup table from 0 to 0.165 V, typ, clamps not added: 45.3 ohm
|   GND clamp passes 1 mA (typ) near -0.49 V on its own axis
|   POWER clamp passes 1 mA (typ) near -0.45 V on its own axis
|   rising waveform, R_fixture 50.000, V_fixture 0.0: 20-80 % time 143ps typ, 161ps min, 142ps max; typ from 0 V to 0.56 V
|   rising waveform, R_fixture 50.000, V_fixture 0.550: 20-80 % time 123ps typ, 140ps min, 120ps max; typ from 0.214 V to 0.837 V
|   falling waveform, R_fixture 50.000, V_fixture 0.550: 20-80 % time 88.1ps typ, 111ps min, 78.4ps max; typ from 0.837 V to 0.214 V
|   falling waveform, R_fixture 50.000, V_fixture 0.0: 20-80 % time 83.9ps typ, 101ps min, 76.4ps max; typ from 0.56 V to 0 V
[Pulldown]
|Voltage   I(typ)   I(min)   I(max)
-1.1V     -13.5mA    -12.25mA   -14.11mA
-998mV    -18.66mA   -16.69mA   -18.05mA
-896mV    -19.4mA    -19mA      -17.81mA
-488mV    -14.84mA   -14.76mA   -13.99mA
1.246V    38.35mA    38.42mA    36.65mA
1.824V    52.74mA    51.53mA    51.2mA
1.926V    54.81mA    50.69mA    53.7mA
2.028V    54.17mA    42.2mA     55.99mA
2.062V    51.67mA    37.77mA    56.33mA
2.13V     41.38mA    29.25mA    53.34mA
2.164V    35.13mA    25.8mA     48.11mA
2.2V      29.25mA    22.8mA     40.19mA
[Pullup]
|Voltage   I(typ)   I(min)   I(max)
-1.1V     4.877mA    5.08mA     3.939mA
-996mV    8.246mA    7.456mA    7.374mA
-894mV    10.69mA    10.28mA    8.55mA
-758mV    10.87mA    11.4mA     8.618mA
-486mV    9.499mA    9.475mA    8.22mA
-316mV    6.88mA     6.811mA    6.248mA
568mV     -11.67mA   -11.87mA   -10.41mA
1.554V    -24.85mA   -26.39mA   -20.64mA
1.792V    -24.51mA   -26.32mA   -19.83mA
1.962V    -23.37mA   -24.66mA   -18.45mA
2.098V    -20.74mA   -18.69mA   -17.05mA
2.2V      -14.17mA   -12.98mA   -13.7mA
[GND_clamp]
|Voltage   I(typ)   I(min)   I(max)
-1.1V     -70.18mA   -84.03mA   -66.29mA
-1.054V   -53mA      -64.11mA   -52.79mA
-1.008V   -41.48mA   -48.48mA   -44.69mA
-962mV    -34.13mA   -37.22mA   -38.96mA
-916mV    -28.9mA    -29.49mA   -33.97mA
-847mV    -22.51mA   -21.79mA   -26.95mA
-778mV    -16.78mA   -16.17mA   -20.25mA
-663mV    -8.429mA   -8.709mA   -10.22mA
-571mV    -3.466mA   -4.237mA   -4.094mA
-502mV    -1.18mA    -1.941mA   -1.256mA
-410mV    -105.5uA   -402.4uA   -63.37uA
1.1V      0A         0A         0A
[POWER_clamp]
|Voltage   I(typ)   I(min)   I(max)
-1.085V   71.41mA    95.35mA    58.18mA
-1.062V   59.23mA    82.55mA    46.99mA
-1.039V   48.36mA    70.56mA    37.71mA
-1.016V   38.97mA    59.53mA    30.53mA
-970mV    25.17mA    40.76mA    21.88mA
-924mV    17.37mA    26.93mA    17.87mA
-901mV    15.03mA    21.86mA    16.59mA
-855mV    12.01mA    14.79mA    14.5mA
-763mV    8.448mA    8.108mA    10.89mA
-533mV    2.369mA    2.267mA    3.272mA
-349mV    143.9uA    291.4uA    171.3uA
1.1V      0A         0A         0A
[Ramp]
| variable   typ   min   max
dV/dt_r   0.336/0.143n   0.330/0.161n   0.323/0.142n
dV/dt_f   0.402/96.151p   0.393/0.125n   0.404/82.776p
R_load = 50.000
[Rising Waveform]
R_fixture= 50.000
V_fixture= 0.0
V_fixture_min= 0.0
V_fixture_max= 0.0
|time   V(typ)   V(min)   V(max)
0s        961.4nV    5.179uV    441nV
365ps     68.67uV    39.26uV    4.864mV
472ps     9.079mV    -303.6uV   247.2mV
558ps     192.8mV    3.916mV    425.9mV
636ps     387.1mV    114.4mV    496.5mV
702ps     485.7mV    264.8mV    520mV
801ps     539mV      447.2mV    532.8mV
914ps     554.7mV    521.9mV    536.5mV
1.391ns   559.6mV    549.1mV    537.6mV
10ns      559.5mV    549.2mV    537.6mV
[Rising Waveform]
R_fixture= 50.000
V_fixture= 0.550
V_fixture_min= 0.534
V_fixture_max= 0.568
|time   V(typ)   V(min)   V(max)
0s        214.4mV    206.4mV    229.1mV
366ps     214.5mV    206.4mV    231.4mV
473ps     220.5mV    206.1mV    520mV
538ps     353.7mV    205.7mV    707.7mV
605ps     583.3mV    253.9mV    798.1mV
677ps     745.9mV    433.8mV    831.4mV
777ps     815.7mV    686.3mV    845.1mV
905ps     833.7mV    790mV      848.6mV
1.181ns   837.4mV    813mV      849.1mV
10ns      837.4mV    813.9mV    849.1mV
[Falling Waveform]
R_fixture= 50.000
V_fixture= 0.550
V_fixture_min= 0.534
V_fixture_max= 0.568
|time   V(typ)   V(min)   V(max)
0s        837.4mV    813.9mV    849.1mV
379ps     837.9mV    813.9mV    844.8mV
404ps     839mV      814.1mV    777.3mV
481ps     830mV      815.8mV    384.4mV
517ps     743.4mV    817.1mV    307.1mV
596ps     381.9mV    779.1mV    250mV
705ps     242.3mV    421mV      233.4mV
817ps     221mV      248.4mV    230.1mV
1.074ns   214.9mV    210mV      229.1mV
10ns      214.4mV    206.4mV    229.1mV
[Falling Waveform]
R_fixture= 50.000
V_fixture= 0.0
V_fixture_min= 0.0
V_fixture_max= 0.0
|time   V(typ)   V(min)   V(max)
0s        559.5mV    549.2mV    537.5mV
373ps     560.5mV    549.3mV    534.3mV
395ps     561.5mV    549.5mV    482.2mV
483ps     537.6mV    552.2mV    107.1mV
558ps     231.4mV    542.7mV    26.39mV
596ps     112.2mV    489.5mV    14.09mV
634ps     54.36mV    368.3mV    7.735mV
714ps     14.45mV    112.3mV    2.357mV
797ps     4.438mV    27.54mV    721.3uV
10ns      958.8nV    5.166uV    443.4nV
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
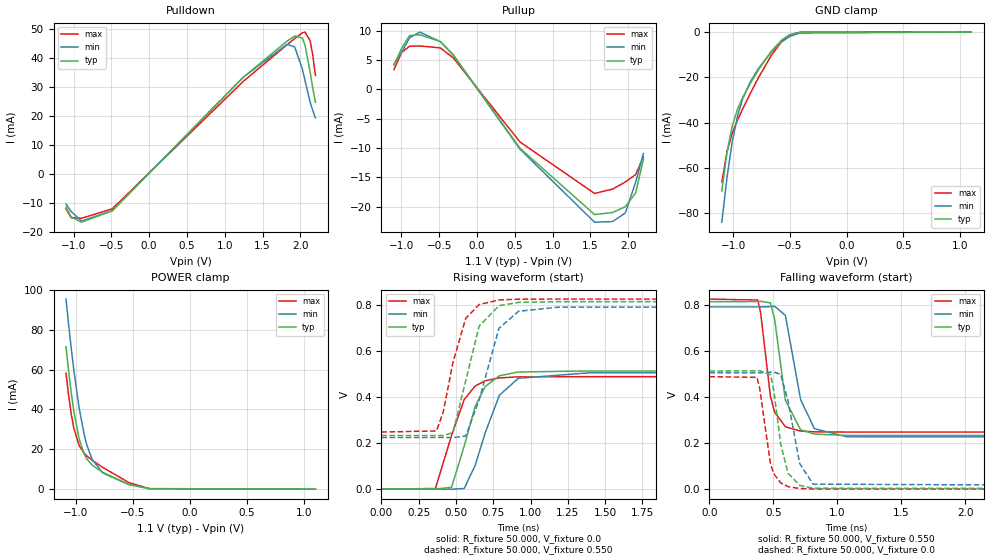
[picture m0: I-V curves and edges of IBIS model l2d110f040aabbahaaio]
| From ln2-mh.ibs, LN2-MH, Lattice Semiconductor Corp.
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|   Model l2d110f040aabbahaaio
[Model] l2d110f040aabbahaaio
| Clamp models do not include dynamic input termination. Please refer to
| the l2d110axxxaabbahaain model for input termination.
Model_type I/O
Polarity   Non-Inverting
Enable   Active-Low
Vinl =  0.200V
Vinh =  0.300V
Vmeas =  0.550V
Cref =  20.000pF
Rref =  50.000
Vref =  0.600V
C_comp   2.000pF   1.500pF   2.500pF
[Temperature Range]   25.000   0.125k   -40.000
[Voltage Range]   1.100V   1.070V   1.130V
[C Comp Corner]
C_comp   2.000pF   1.500pF   2.500pF
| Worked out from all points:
|   slope of the pulldown table from 0 to 0.165 V, typ, clamps not added: 36.9 ohm
|   slope of the pullup table from 0 to 0.165 V, typ, clamps not added: 52.6 ohm
|   GND clamp passes 1 mA (typ) near -0.49 V on its own axis
|   POWER clamp passes 1 mA (typ) near -0.45 V on its own axis
|   rising waveform, R_fixture 50.000, V_fixture 0.0: 20-80 % time 141ps typ, 160ps min, 142ps max; typ from 0 V to 0.515 V
|   rising waveform, R_fixture 50.000, V_fixture 0.550: 20-80 % time 119ps typ, 136ps min, 119ps max; typ from 0.233 V to 0.816 V
|   falling waveform, R_fixture 50.000, V_fixture 0.550: 20-80 % time 90.4ps typ, 114ps min, 81.4ps max; typ from 0.816 V to 0.233 V
|   falling waveform, R_fixture 50.000, V_fixture 0.0: 20-80 % time 84.6ps typ, 103ps min, 79ps max; typ from 0.515 V to 0 V
[Pulldown]
|Voltage   I(typ)   I(min)   I(max)
-1.1V     -11.54mA   -10.46mA   -12.1mA
-1.032V   -14.95mA   -13.05mA   -15.15mA
-896mV    -16.75mA   -16.38mA   -15.42mA
-488mV    -12.84mA   -12.77mA   -12.13mA
1.246V    33.22mA    33.26mA    31.81mA
1.824V    45.66mA    44.54mA    44.41mA
1.926V    47.43mA    43.65mA    46.57mA
2.028V    46.68mA    35.94mA    48.54mA
2.062V    44.32mA    32.03mA    48.79mA
2.13V     35mA       24.68mA    45.83mA
2.164V    29.56mA    21.75mA    40.94mA
2.2V      24.55mA    19.2mA     33.8mA
[Pullup]
|Voltage   I(typ)   I(min)   I(max)
-1.1V     4.135mA    4.293mA    3.355mA
-996mV    7.03mA     6.335mA    6.319mA
-894mV    9.159mA    8.781mA    7.344mA
-758mV    9.324mA    9.763mA    7.4mA
-486mV    8.157mA    8.13mA     7.064mA
-316mV    5.917mA    5.851mA    5.381mA
568mV     -10.04mA   -10.2mA    -8.966mA
1.554V    -21.34mA   -22.64mA   -17.74mA
1.792V    -20.99mA   -22.53mA   -17mA
1.962V    -19.99mA   -21.06mA   -15.79mA
2.098V    -17.64mA   -15.83mA   -14.52mA
2.2V      -11.93mA   -10.94mA   -11.52mA
[GND_clamp]
|Voltage   I(typ)   I(min)   I(max)
-1.1V     -70.17mA   -84.03mA   -66.28mA
-1.054V   -53mA      -64.11mA   -52.78mA
-1.008V   -41.48mA   -48.48mA   -44.68mA
-962mV    -34.13mA   -37.21mA   -38.95mA
-916mV    -28.9mA    -29.48mA   -33.97mA
-847mV    -22.51mA   -21.79mA   -26.94mA
-778mV    -16.78mA   -16.17mA   -20.25mA
-663mV    -8.429mA   -8.708mA   -10.22mA
-571mV    -3.466mA   -4.237mA   -4.093mA
-502mV    -1.18mA    -1.941mA   -1.256mA
-410mV    -105.5uA   -402.4uA   -63.37uA
1.1V      0A         0A         0A
[POWER_clamp]
|Voltage   I(typ)   I(min)   I(max)
-1.085V   71.41mA    95.35mA    58.18mA
-1.062V   59.23mA    82.55mA    46.99mA
-1.039V   48.36mA    70.56mA    37.71mA
-1.016V   38.97mA    59.53mA    30.53mA
-970mV    25.17mA    40.76mA    21.88mA
-924mV    17.37mA    26.93mA    17.87mA
-901mV    15.03mA    21.86mA    16.59mA
-855mV    12.01mA    14.79mA    14.5mA
-763mV    8.448mA    8.108mA    10.89mA
-533mV    2.369mA    2.267mA    3.272mA
-349mV    143.9uA    291.4uA    171.3uA
1.1V      0A         0A         0A
[Ramp]
| variable   typ   min   max
dV/dt_r   0.309/0.141n   0.304/0.160n   0.294/0.142n
dV/dt_f   0.379/98.588p   0.371/0.128n   0.381/85.461p
R_load = 50.000
[Rising Waveform]
R_fixture= 50.000
V_fixture= 0.0
V_fixture_min= 0.0
V_fixture_max= 0.0
|time   V(typ)   V(min)   V(max)
0s        1.068uV    5.74uV     488.6nV
362ps     71.39uV    43.11uV    2.74mV
470ps     7.745mV    -252.5uV   233.3mV
555ps     187.5mV    2.822mV    390.2mV
629ps     361mV      104.2mV    449.3mV
696ps     447.1mV    245.6mV    471.9mV
791ps     493.7mV    408.9mV    484.4mV
918ps     510.2mV    482.7mV    488.9mV
1.389ns   514.6mV    506.4mV    490mV
10ns      514.6mV    506.5mV    490mV
[Rising Waveform]
R_fixture= 50.000
V_fixture= 0.550
V_fixture_min= 0.534
V_fixture_max= 0.568
|time   V(typ)   V(min)   V(max)
0s        233.5mV    224.9mV    248.7mV
369ps     233.5mV    225mV      253.2mV
414ps     233.1mV    225mV      335.2mV
480ps     246.4mV    224.5mV    553mV
565ps     472.1mV    231.1mV    743.5mV
655ps     709.8mV    388mV      803.8mV
788ps     799mV      700.5mV    824mV
920ps     813.4mV    774.7mV    827.3mV
1.184ns   816.5mV    792.5mV    827.8mV
10ns      816.5mV    793.4mV    827.8mV
[Falling Waveform]
R_fixture= 50.000
V_fixture= 0.550
V_fixture_min= 0.534
V_fixture_max= 0.568
|time   V(typ)   V(min)   V(max)
0s        816.4mV    793.4mV    827.8mV
378ps     817mV      793.4mV    823.6mV
400ps     817.8mV    793.6mV    770.6mV
477ps     811.2mV    795.1mV    405.1mV
510ps     740.5mV    796.4mV    335.6mV
594ps     387.1mV    756.9mV    271.5mV
713ps     258.4mV    389.9mV    252.9mV
821ps     239.9mV    263.4mV    249.7mV
1.072ns   233.9mV    228.4mV    248.7mV
10ns      233.5mV    224.9mV    248.7mV
[Falling Waveform]
R_fixture= 50.000
V_fixture= 0.0
V_fixture_min= 0.0
V_fixture_max= 0.0
|time   V(typ)   V(min)   V(max)
0s        514.6mV    506.5mV    489.9mV
372ps     515.5mV    506.6mV    486.8mV
392ps     516.4mV    506.8mV    443mV
478ps     498.3mV    509.3mV    107.8mV
504ps     428.2mV    510.1mV    67.01mV
557ps     197.6mV    499.8mV    27.44mV
615ps     69.09mV    383.6mV    11.18mV
706ps     16.47mV    110.8mV    2.994mV
811ps     3.938mV    21.92mV    698.2uV
10ns      1.067uV    5.729uV    492.2nV
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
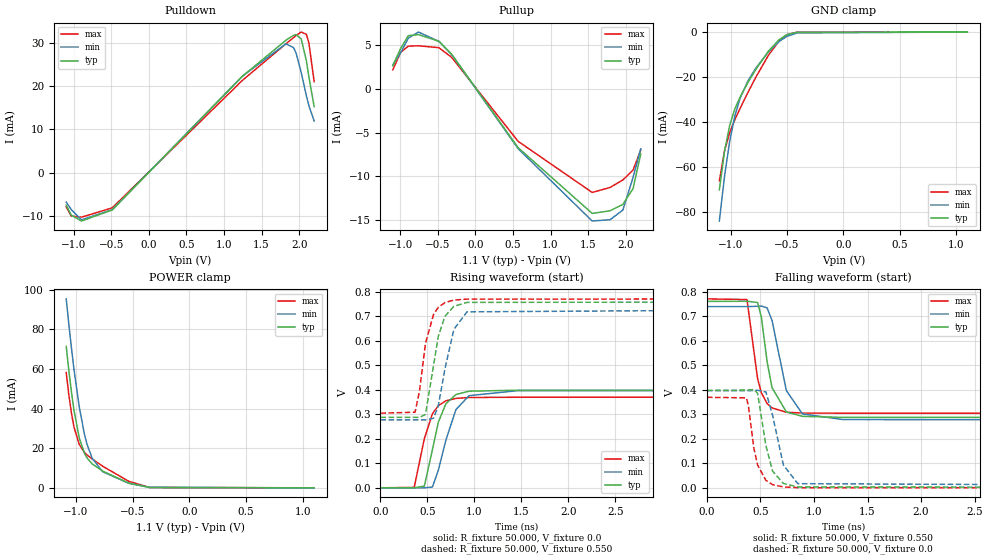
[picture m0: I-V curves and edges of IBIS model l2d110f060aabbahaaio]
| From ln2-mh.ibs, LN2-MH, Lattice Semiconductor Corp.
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|   Model l2d110f060aabbahaaio
[Model] l2d110f060aabbahaaio
| Clamp models do not include dynamic input termination. Please refer to
| the l2d110axxxaabbahaain model for input termination.
Model_type I/O
Polarity   Non-Inverting
Enable   Active-Low
Vinl =  0.200V
Vinh =  0.300V
Vmeas =  0.550V
Cref =  20.000pF
Rref =  50.000
Vref =  0.600V
C_comp   2.000pF   1.500pF   2.500pF
[Temperature Range]   25.000   0.125k   -40.000
[Voltage Range]   1.100V   1.070V   1.130V
[C Comp Corner]
C_comp   2.000pF   1.500pF   2.500pF
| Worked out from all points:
|   slope of the pulldown table from 0 to 0.165 V, typ, clamps not added: 54.8 ohm
|   slope of the pullup table from 0 to 0.165 V, typ, clamps not added: 78.5 ohm
|   GND clamp passes 1 mA (typ) near -0.49 V on its own axis
|   POWER clamp passes 1 mA (typ) near -0.45 V on its own axis
|   rising waveform, R_fixture 50.000, V_fixture 0.0: 20-80 % time 149ps typ, 179ps min, 142ps max; typ from 0 V to 0.398 V
|   rising waveform, R_fixture 50.000, V_fixture 0.550: 20-80 % time 123ps typ, 145ps min, 117ps max; typ from 0.288 V to 0.762 V
|   falling waveform, R_fixture 50.000, V_fixture 0.550: 20-80 % time 108ps typ, 139ps min, 92.9ps max; typ from 0.762 V to 0.288 V
|   falling waveform, R_fixture 50.000, V_fixture 0.0: 20-80 % time 99.1ps typ, 122ps min, 89.8ps max; typ from 0.398 V to 0 V
[Pulldown]
|Voltage   I(typ)   I(min)   I(max)
-1.1V     -7.499mA   -6.787mA   -7.895mA
-1.032V   -9.836mA   -8.546mA   -10.04mA
-896mV    -11.17mA   -10.89mA   -10.28mA
-488mV    -8.614mA   -8.561mA   -8.134mA
1.246V    22.32mA    22.34mA    21.37mA
1.824V    30.63mA    29.8mA     29.8mA
1.926V    31.78mA    28.92mA    31.25mA
1.96V     31.94mA    27.63mA    31.73mA
2.028V    30.91mA    23.16mA    32.53mA
2.096V    25.92mA    17.81mA    32mA
2.13V     22.15mA    15.51mA    29.99mA
2.2V      15.25mA    11.94mA    21.05mA
[Pullup]
|Voltage   I(typ)   I(min)   I(max)
-1.1V     2.659mA    2.739mA    2.174mA
-996mV    4.615mA    4.123mA    4.178mA
-894mV    6.091mA    5.806mA    4.892mA
-758mV    6.217mA    6.508mA    4.932mA
-486mV    5.452mA    5.436mA    4.716mA
-316mV    3.967mA    3.921mA    3.605mA
568mV     -6.721mA   -6.835mA   -6mA
1.554V    -14.25mA   -15.12mA   -11.85mA
1.792V    -13.95mA   -14.97mA   -11.28mA
1.962V    -13.22mA   -13.87mA   -10.42mA
2.098V    -11.41mA   -10.13mA   -9.293mA
2.2V      -7.455mA   -6.863mA   -6.994mA
[GND_clamp]
|Voltage   I(typ)   I(min)   I(max)
-1.1V     -70.16mA   -84.02mA   -66.23mA
-1.054V   -52.99mA   -64.1mA    -52.74mA
-1.008V   -41.46mA   -48.47mA   -44.65mA
-962mV    -34.12mA   -37.21mA   -38.93mA
-916mV    -28.89mA   -29.48mA   -33.95mA
-847mV    -22.5mA    -21.78mA   -26.93mA
-778mV    -16.78mA   -16.17mA   -20.24mA
-663mV    -8.428mA   -8.707mA   -10.21mA
-571mV    -3.466mA   -4.237mA   -4.093mA
-502mV    -1.179mA   -1.94mA    -1.256mA
-410mV    -105.5uA   -402.4uA   -63.37uA
1.1V      0A         0A         0A
[POWER_clamp]
|Voltage   I(typ)   I(min)   I(max)
-1.085V   71.41mA    95.35mA    58.18mA
-1.062V   59.23mA    82.55mA    46.99mA
-1.039V   48.36mA    70.56mA    37.71mA
-1.016V   38.97mA    59.53mA    30.53mA
-970mV    25.17mA    40.76mA    21.88mA
-924mV    17.37mA    26.93mA    17.87mA
-901mV    15.03mA    21.86mA    16.59mA
-855mV    12.01mA    14.79mA    14.5mA
-763mV    8.448mA    8.108mA    10.89mA
-533mV    2.369mA    2.267mA    3.272mA
-349mV    143.9uA    291.4uA    171.3uA
1.1V      0A         0A         0A
[Ramp]
| variable   typ   min   max
dV/dt_r   0.239/0.149n   0.238/0.179n   0.222/0.142n
dV/dt_f   0.314/0.119n   0.307/0.161n   0.314/97.263p
R_load = 50.000
[Rising Waveform]
R_fixture= 50.000
V_fixture= 0.0
V_fixture_min= 0.0
V_fixture_max= 0.0
|time   V(typ)   V(min)   V(max)
0s        1.37uV     7.322uV    623.3nV
360ps     78.34uV    58.06uV    1.658mV
468ps     6.942mV    -192.8uV   200.7mV
554ps     155.7mV    3.244mV    302.6mV
617ps     268mV      71.82mV    335.8mV
697ps     343.2mV    194.3mV    355.3mV
804ps     381mV      319.4mV    365.1mV
944ps     394.6mV    376.4mV    368.9mV
1.452ns   398.6mV    396.4mV    369.9mV
10ns      398.5mV    396.5mV    369.8mV
[Rising Waveform]
R_fixture= 50.000
V_fixture= 0.550
V_fixture_min= 0.534
V_fixture_max= 0.568
|time   V(typ)   V(min)   V(max)
0s        287.8mV    277.7mV    304.9mV
369ps     287.9mV    277.7mV    308.8mV
416ps     287.5mV    277.7mV    394mV
480ps     299.8mV    277.3mV    589.2mV
566ps     499.4mV    284.2mV    708.5mV
617ps     619.5mV    335.7mV    737.3mV
687ps     700.6mV    485.9mV    756.6mV
783ps     741.5mV    647.7mV    766.9mV
922ps     757.4mV    718.8mV    770.9mV
10ns      761.5mV    740.2mV    771.8mV
[Falling Waveform]
R_fixture= 50.000
V_fixture= 0.550
V_fixture_min= 0.534
V_fixture_max= 0.568
|time   V(typ)   V(min)   V(max)
0s        761.5mV    740.2mV    771.8mV
374ps     762mV      740.2mV    769mV
473ps     757.1mV    741.6mV    446.2mV
508ps     698.2mV    742.5mV    389mV
562ps     515.6mV    735.1mV    344.4mV
608ps     409.4mV    683.5mV    326.4mV
742ps     310mV      397.2mV    308.8mV
892ps     291.9mV    301.9mV    305.5mV
1.274ns   287.8mV    278.7mV    304.9mV
10ns      287.8mV    277.6mV    304.9mV
[Falling Waveform]
R_fixture= 50.000
V_fixture= 0.0
V_fixture_min= 0.0
V_fixture_max= 0.0
|time   V(typ)   V(min)   V(max)
0s        398.5mV    396.5mV    369.8mV
369ps     399.3mV    396.5mV    367.5mV
388ps     400mV      396.7mV    333mV
438ps     401.2mV    397.5mV    162.3mV
473ps     386.6mV    398.7mV    93.45mV
551ps     172.4mV    391.6mV    30.29mV
613ps     68.51mV    296.1mV    13.22mV
714ps     17.86mV    93.19mV    3.689mV
849ps     3.568mV    16.95mV    754.2uV
10ns      1.371uV    7.318uV    629.7nV
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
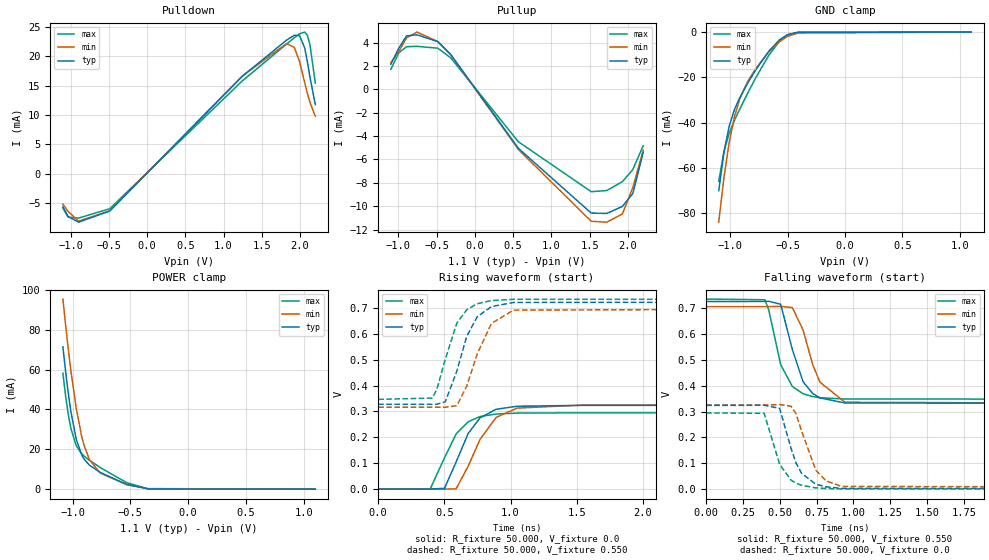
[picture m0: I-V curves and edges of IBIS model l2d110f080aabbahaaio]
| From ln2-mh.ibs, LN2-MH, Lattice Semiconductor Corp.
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|   Model l2d110f080aabbahaaio
[Model] l2d110f080aabbahaaio
| Clamp models do not include dynamic input termination. Please refer to
| the l2d110axxxaabbahaain model for input termination.
Model_type I/O
Polarity   Non-Inverting
Enable   Active-Low
Vinl =  0.200V
Vinh =  0.300V
Vmeas =  0.550V
Cref =  20.000pF
Rref =  50.000
Vref =  0.600V
C_comp   2.000pF   1.500pF   2.500pF
[Temperature Range]   25.000   0.125k   -40.000
[Voltage Range]   1.100V   1.070V   1.130V
[C Comp Corner]
C_comp   2.000pF   1.500pF   2.500pF
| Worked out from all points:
|   slope of the pulldown table from 0 to 0.165 V, typ, clamps not added: 73.8 ohm
|   slope of the pullup table from 0 to 0.165 V, typ, clamps not added: 104 ohm
|   GND clamp passes 1 mA (typ) near -0.49 V on its own axis
|   POWER clamp passes 1 mA (typ) near -0.45 V on its own axis
|   rising waveform, R_fixture 50.000, V_fixture 0.0: 20-80 % time 178ps typ, 195ps min, 171ps max; typ from 0 V to 0.324 V
|   rising waveform, R_fixture 50.000, V_fixture 0.550: 20-80 % time 154ps typ, 170ps min, 144ps max; typ from 0.328 V to 0.725 V
|   falling waveform, R_fixture 50.000, V_fixture 0.550: 20-80 % time 121ps typ, 142ps min, 111ps max; typ from 0.725 V to 0.328 V
|   falling waveform, R_fixture 50.000, V_fixture 0.0: 20-80 % time 112ps typ, 124ps min, 105ps max; typ from 0.324 V to 0 V
[Pulldown]
|Voltage   I(typ)   I(min)   I(max)
-1.1V     -5.675mA   -5.241mA   -5.881mA
-1.032V   -7.334mA   -6.457mA   -7.433mA
-896mV    -8.3mA     -8.119mA   -7.6mA
-488mV    -6.4mA     -6.37mA    -6.008mA
1.246V    16.59mA    16.63mA    15.8mA
1.824V    22.74mA    22.16mA    22.07mA
1.926V    23.59mA    21.49mA    23.15mA
1.994V    23.53mA    19.11mA    23.83mA
2.062V    21.38mA    15.45mA    24.12mA
2.096V    19.11mA    13.68mA    23.59mA
2.13V     16.44mA    12.14mA    21.98mA
2.2V      11.76mA    9.772mA    15.43mA
[Pullup]
|Voltage   I(typ)   I(min)   I(max)
-1.1V     2.15mA     2.287mA    1.709mA
-996mV    3.524mA    3.244mA    3.134mA
-894mV    4.58mA     4.417mA    3.654mA
-758mV    4.67mA     4.905mA    3.687mA
-486mV    4.097mA    4.096mA    3.528mA
-316mV    2.983mA    2.956mA    2.698mA
568mV     -5.048mA   -5.147mA   -4.484mA
1.52V     -10.59mA   -11.29mA   -8.759mA
1.724V    -10.62mA   -11.37mA   -8.658mA
1.928V    -10.02mA   -10.66mA   -7.895mA
2.064V    -8.913mA   -8.407mA   -6.86mA
2.2V      -5.376mA   -5.209mA   -4.823mA
[GND_clamp]
|Voltage   I(typ)   I(min)   I(max)
-1.1V     -70.14mA   -84.01mA   -65.93mA
-1.054V   -52.97mA   -64.09mA   -52.57mA
-1.008V   -41.45mA   -48.46mA   -44.57mA
-962mV    -34.1mA    -37.2mA    -38.89mA
-916mV    -28.88mA   -29.47mA   -33.93mA
-847mV    -22.5mA    -21.78mA   -26.92mA
-778mV    -16.77mA   -16.16mA   -20.24mA
-663mV    -8.426mA   -8.706mA   -10.21mA
-571mV    -3.465mA   -4.236mA   -4.092mA
-502mV    -1.179mA   -1.94mA    -1.256mA
-410mV    -105.5uA   -402.4uA   -63.37uA
1.1V      0A         0A         0A
[POWER_clamp]
|Voltage   I(typ)   I(min)   I(max)
-1.085V   71.41mA    95.35mA    58.18mA
-1.062V   59.23mA    82.55mA    46.99mA
-1.039V   48.36mA    70.56mA    37.71mA
-1.016V   38.97mA    59.53mA    30.53mA
-970mV    25.17mA    40.76mA    21.88mA
-924mV    17.37mA    26.93mA    17.87mA
-901mV    15.03mA    21.86mA    16.59mA
-855mV    12.01mA    14.79mA    14.5mA
-763mV    8.448mA    8.108mA    10.89mA
-533mV    2.369mA    2.267mA    3.272mA
-349mV    143.9uA    291.4uA    171.3uA
1.1V      0A         0A         0A
[Ramp]
| variable   typ   min   max
dV/dt_r   0.194/0.178n   0.195/0.195n   0.177/0.171n
dV/dt_f   0.266/0.134n   0.261/0.163n   0.264/0.120n
R_load = 50.000
[Rising Waveform]
R_fixture= 50.000
V_fixture= 0.0
V_fixture_min= 0.0
V_fixture_max= 0.0
|time   V(typ)   V(min)   V(max)
0s        1.59uV     8.481uV    722.6nV
393ps     195.6uV    112uV      626.7uV
501ps     3.021mV    -271.8uV   120.8mV
589ps     105mV      1.047mV    213.2mV
680ps     214.9mV    88.85mV    260.3mV
769ps     275.2mV    191.6mV    280.2mV
891ps     308.4mV    277mV      290.2mV
1.049ns   320.2mV    313mV      293.8mV
1.552ns   323.6mV    325mV      294.7mV
10ns      323.6mV    325mV      294.6mV
[Rising Waveform]
R_fixture= 50.000
V_fixture= 0.550
V_fixture_min= 0.534
V_fixture_max= 0.568
|time   V(typ)   V(min)   V(max)
0s        328mV      316.5mV    346.8mV
409ps     327.9mV    316.6mV    351.8mV
443ps     327.8mV    316.7mV    385.4mV
507ps     337.4mV    316.4mV    501.7mV
594ps     455.7mV    322.2mV    641.5mV
669ps     590.3mV    397.6mV    692.8mV
748ps     665.9mV    522.1mV    716.3mV
856ps     705.4mV    640.5mV    728.7mV
1.023ns   721.4mV    691.8mV    733.5mV
10ns      724.9mV    705.1mV    734.4mV
[Falling Waveform]
R_fixture= 50.000
V_fixture= 0.550
V_fixture_min= 0.534
V_fixture_max= 0.568
|time   V(typ)   V(min)   V(max)
0s        724.9mV    705.1mV    734.4mV
399ps     725.2mV    705.1mV    731.7mV
425ps     725.9mV    705.2mV    692.4mV
506ps     714.3mV    706.3mV    481mV
585ps     539.9mV    701.4mV    396.8mV
658ps     415.3mV    615mV      368.5mV
723ps     369.6mV    481.3mV    357.7mV
773ps     352.5mV    413mV      353.4mV
942ps     333mV      335.8mV    348.2mV
10ns      328mV      316.5mV    346.8mV
[Falling Waveform]
R_fixture= 50.000
V_fixture= 0.0
V_fixture_min= 0.0
V_fixture_max= 0.0
|time   V(typ)   V(min)   V(max)
0s        323.6mV    325mV      294.6mV
394ps     324.2mV    325mV      293mV
499ps     312.1mV    326.7mV    95.56mV
576ps     158.3mV    320.5mV    34.98mV
609ps     102.4mV    293.1mV    23.38mV
648ps     61.01mV    224.7mV    14.8mV
744ps     19.26mV    73.7mV     5.112mV
812ps     9.167mV    32.86mV    2.585mV
918ps     3.154mV    10.72mV    1.011mV
10ns      1.59uV     8.473uV    731.1nV
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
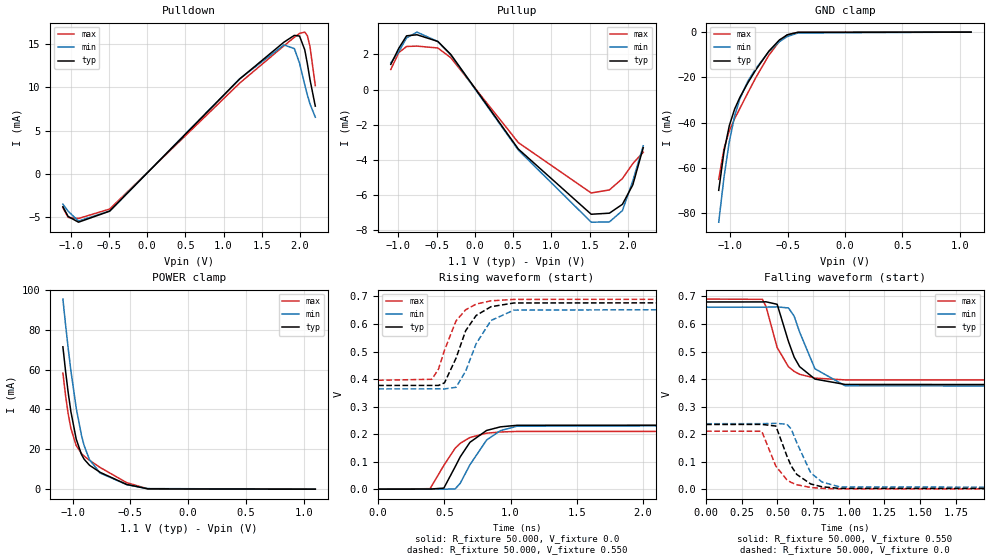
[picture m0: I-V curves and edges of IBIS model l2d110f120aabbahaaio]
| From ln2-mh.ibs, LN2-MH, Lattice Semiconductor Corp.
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|   Model l2d110f120aabbahaaio
[Model] l2d110f120aabbahaaio
| Clamp models do not include dynamic input termination. Please refer to
| the l2d110axxxaabbahaain model for input termination.
Model_type I/O
Polarity   Non-Inverting
Enable   Active-Low
Vinl =  0.200V
Vinh =  0.300V
Vmeas =  0.550V
Cref =  20.000pF
Rref =  50.000
Vref =  0.600V
C_comp   2.000pF   1.500pF   2.500pF
[Temperature Range]   25.000   0.125k   -40.000
[Voltage Range]   1.100V   1.070V   1.130V
[C Comp Corner]
C_comp   2.000pF   1.500pF   2.500pF
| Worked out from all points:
|   slope of the pulldown table from 0 to 0.165 V, typ, clamps not added: 108 ohm
|   slope of the pullup table from 0 to 0.165 V, typ, clamps not added: 156 ohm
|   GND clamp passes 1 mA (typ) near -0.49 V on its own axis
|   POWER clamp passes 1 mA (typ) near -0.45 V on its own axis
|   rising waveform, R_fixture 50.000, V_fixture 0.0: 20-80 % time 183ps typ, 197ps min, 179ps max; typ from 0 V to 0.235 V
|   rising waveform, R_fixture 50.000, V_fixture 0.550: 20-80 % time 159ps typ, 174ps min, 148ps max; typ from 0.377 V to 0.68 V
|   falling waveform, R_fixture 50.000, V_fixture 0.550: 20-80 % time 132ps typ, 148ps min, 124ps max; typ from 0.68 V to 0.377 V
|   falling waveform, R_fixture 50.000, V_fixture 0.0: 20-80 % time 123ps typ, 133ps min, 119ps max; typ from 0.235 V to 0 V
[Pulldown]
|Voltage   I(typ)   I(min)   I(max)
-1.1V     -3.828mA   -3.534mA   -3.948mA
-1.032V   -4.961mA   -4.354mA   -5.077mA
-896mV    -5.627mA   -5.495mA   -5.197mA
-488mV    -4.347mA   -4.322mA   -4.101mA
1.212V    10.98mA    11mA       10.5mA
1.79V     15.24mA    14.92mA    14.82mA
1.926V    16.03mA    14.5mA     15.8mA
1.994V    15.95mA    12.81mA    16.26mA
2.062V    14.36mA    10.31mA    16.41mA
2.096V    12.76mA    9.126mA    15.99mA
2.13V     10.93mA    8.106mA    14.77mA
2.2V      7.825mA    6.542mA    10.21mA
[Pullup]
|Voltage   I(typ)   I(min)   I(max)
-1.1V     1.431mA    1.519mA    1.144mA
-996mV    2.344mA    2.153mA    2.098mA
-894mV    3.054mA    2.935mA    2.449mA
-758mV    3.115mA    3.266mA    2.469mA
-486mV    2.737mA    2.731mA    2.364mA
-316mV    1.997mA    1.974mA    1.813mA
568mV     -3.38mA    -3.44mA    -3.014mA
1.52V     -7.081mA   -7.532mA   -5.872mA
1.758V    -7.02mA    -7.517mA   -5.699mA
1.928V    -6.516mA   -6.874mA   -5.056mA
2.064V    -5.413mA   -5.187mA   -4.203mA
2.2V      -3.301mA   -3.193mA   -3.558mA
[GND_clamp]
|Voltage   I(typ)   I(min)   I(max)
-1.1V     -69.86mA   -83.93mA   -64.98mA
-1.054V   -52.78mA   -64.04mA   -51.45mA
-1.008V   -41.35mA   -48.42mA   -43.59mA
-962mV    -34.05mA   -37.17mA   -38.31mA
-916mV    -28.85mA   -29.45mA   -33.73mA
-847mV    -22.48mA   -21.76mA   -26.88mA
-778mV    -16.77mA   -16.16mA   -20.22mA
-663mV    -8.423mA   -8.703mA   -10.21mA
-571mV    -3.464mA   -4.235mA   -4.09mA
-502mV    -1.179mA   -1.94mA    -1.256mA
-410mV    -105.5uA   -402.4uA   -63.37uA
1.1V      0A         0A         0A
[POWER_clamp]
|Voltage   I(typ)   I(min)   I(max)
-1.085V   71.41mA    95.35mA    58.18mA
-1.062V   59.23mA    82.55mA    46.99mA
-1.039V   48.36mA    70.56mA    37.71mA
-1.016V   38.97mA    59.53mA    30.53mA
-970mV    25.17mA    40.76mA    21.88mA
-924mV    17.37mA    26.93mA    17.87mA
-901mV    15.03mA    21.86mA    16.59mA
-855mV    12.01mA    14.79mA    14.5mA
-763mV    8.448mA    8.108mA    10.89mA
-533mV    2.369mA    2.267mA    3.272mA
-349mV    143.9uA    291.4uA    171.3uA
1.1V      0A         0A         0A
[Ramp]
| variable   typ   min   max
dV/dt_r   0.141/0.183n   0.143/0.197n   0.126/0.179n
dV/dt_f   0.207/0.145n   0.203/0.169n   0.205/0.133n
R_load = 50.000
[Rising Waveform]
R_fixture= 50.000
V_fixture= 0.0
V_fixture_min= 0.0
V_fixture_max= 0.0
|time   V(typ)   V(min)   V(max)
0s        1.863uV    9.921uV    840.8nV
392ps     235.7uV    122.2uV    1.628mV
496ps     3.74mV     -102.6uV   86.23mV
581ps     80.71mV    564.3uV    148.4mV
620ps     117.4mV    21.46mV    166.4mV
693ps     170.1mV    88.29mV    187.6mV
819ps     213.2mV    178.4mV    203.3mV
923ps     226.2mV    212.3mV    207.7mV
1.049ns   232mV      228.8mV    209.7mV
10ns      234.9mV    237.8mV    210.7mV
[Rising Waveform]
R_fixture= 50.000
V_fixture= 0.550
V_fixture_min= 0.534
V_fixture_max= 0.568
|time   V(typ)   V(min)   V(max)
0s        376.7mV    364.2mV    395.6mV
406ps     376.8mV    364.3mV    399.1mV
456ps     376.8mV    364.4mV    436.6mV
501ps     386.3mV    364.1mV    504.7mV
588ps     475.5mV    370.1mV    611.1mV
661ps     575.6mV    428.6mV    651.7mV
740ps     630.9mV    528.2mV    672.3mV
852ps     662.8mV    612.6mV    684.2mV
1.026ns   676.4mV    650.5mV    689.4mV
10ns      680mV      661.3mV    690.6mV
[Falling Waveform]
R_fixture= 50.000
V_fixture= 0.550
V_fixture_min= 0.534
V_fixture_max= 0.568
|time   V(typ)   V(min)   V(max)
0s        680mV      661.3mV    690.6mV
395ps     680.2mV    661.3mV    689.5mV
420ps     680.6mV    661.3mV    663.4mV
498ps     671.6mV    662.2mV    514.4mV
577ps     536.7mV    658.3mV    444.8mV
617ps     479.8mV    628.8mV    427.8mV
655ps     445.2mV    570.9mV    417.4mV
763ps     399.9mV    437.3mV    403.4mV
973ps     380.5mV    376mV      397mV
10ns      376.7mV    364.2mV    395.6mV
[Falling Waveform]
R_fixture= 50.000
V_fixture= 0.0
V_fixture_min= 0.0
V_fixture_max= 0.0
|time   V(typ)   V(min)   V(max)
0s        234.9mV    237.8mV    210.7mV
390ps     235.3mV    237.9mV    210.3mV
489ps     229.3mV    239mV      83.43mV
566ps     120.7mV    235.9mV    34.08mV
596ps     84.63mV    219.2mV    24.51mV
635ps     53.75mV    169.4mV    16.19mV
733ps     18.87mV    59.41mV    5.997mV
813ps     8.594mV    25.81mV    2.867mV
936ps     2.83mV     8.203mV    1.105mV
10ns      1.865uV    9.918uV    852.7nV
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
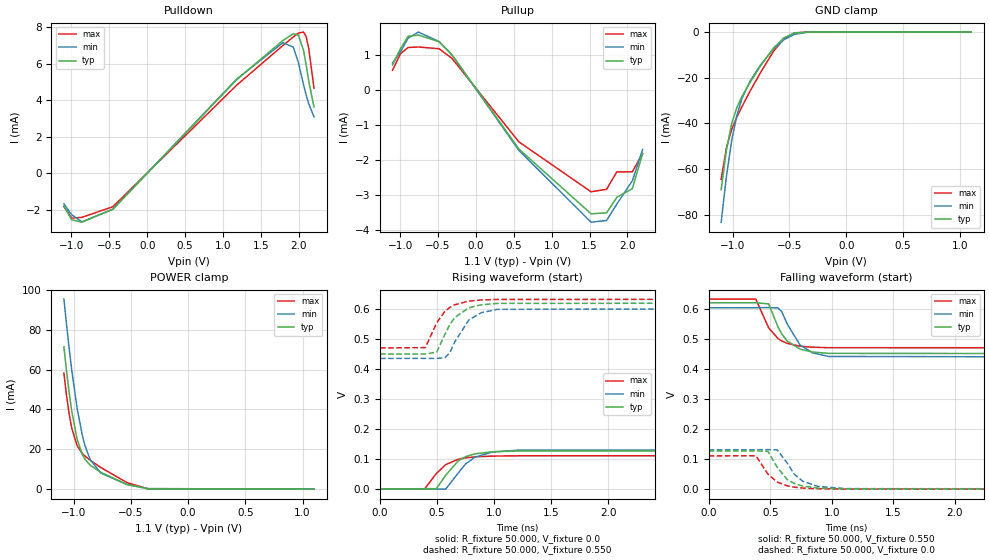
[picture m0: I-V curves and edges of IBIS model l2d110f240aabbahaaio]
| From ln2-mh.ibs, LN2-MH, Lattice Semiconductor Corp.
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|   Model l2d110f240aabbahaaio
[Model] l2d110f240aabbahaaio
| Clamp models do not include dynamic input termination. Please refer to
| the l2d110axxxaabbahaain model for input termination.
Model_type I/O
Polarity   Non-Inverting
Enable   Active-Low
Vinl =  0.200V
Vinh =  0.300V
Vmeas =  0.550V
Cref =  20.000pF
Rref =  50.000
Vref =  0.600V
C_comp   2.000pF   1.500pF   2.500pF
[Temperature Range]   25.000   0.125k   -40.000
[Voltage Range]   1.100V   1.070V   1.130V
[C Comp Corner]
C_comp   2.000pF   1.500pF   2.500pF
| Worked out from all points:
|   slope of the pulldown table from 0 to 0.165 V, typ, clamps not added: 226 ohm
|   slope of the pullup table from 0 to 0.165 V, typ, clamps not added: 313 ohm
|   GND clamp passes 1 mA (typ) near -0.49 V on its own axis
|   POWER clamp passes 1 mA (typ) near -0.45 V on its own axis
|   rising waveform, R_fixture 50.000, V_fixture 0.0: 20-80 % time 175ps typ, 186ps min, 168ps max; typ from 0 V to 0.128 V
|   rising waveform, R_fixture 50.000, V_fixture 0.550: 20-80 % time 160ps typ, 170ps min, 153ps max; typ from 0.451 V to 0.623 V
|   falling waveform, R_fixture 50.000, V_fixture 0.550: 20-80 % time 145ps typ, 158ps min, 139ps max; typ from 0.623 V to 0.451 V
|   falling waveform, R_fixture 50.000, V_fixture 0.0: 20-80 % time 142ps typ, 150ps min, 137ps max; typ from 0.128 V to 0 V
[Pulldown]
|Voltage   I(typ)   I(min)   I(max)
-1.1V     -1.799mA   -1.677mA   -1.823mA
-998mV    -2.552mA   -2.276mA   -2.459mA
-862mV    -2.684mA   -2.662mA   -2.419mA
-454mV    -1.973mA   -1.972mA   -1.836mA
1.178V    5.12mA     5.154mA    4.82mA
1.79V     7.277mA    7.157mA    7.001mA
1.926V    7.641mA    6.913mA    7.467mA
1.994V    7.572mA    6.061mA    7.683mA
2.062V    6.74mA     4.852mA    7.735mA
2.096V    5.944mA    4.292mA    7.494mA
2.13V     5.072mA    3.814mA    6.855mA
2.2V      3.635mA    3.086mA    4.66mA
[Pullup]
|Voltage   I(typ)   I(min)   I(max)
-1.1V     709.3uA    760.2uA    557.1uA
-996mV    1.163mA    1.078mA    1.025mA
-894mV    1.523mA    1.472mA    1.204mA
-758mV    1.557mA    1.642mA    1.218mA
-486mV    1.368mA    1.374mA    1.168mA
-316mV    997.2uA    993.3uA    894.4uA
568mV     -1.684mA   -1.725mA   -1.482mA
1.52V     -3.527mA   -3.765mA   -2.9mA
1.724V    -3.5mA     -3.717mA   -2.829mA
1.86V     -3.057mA   -3.249mA   -2.334mA
2.064V    -2.812mA   -2.59mA    -2.331mA
2.2V      -1.812mA   -1.697mA   -1.811mA
[GND_clamp]
|Voltage   I(typ)   I(min)   I(max)
-1.1V     -69.04mA   -83.29mA   -64.5mA
-1.054V   -51.76mA   -63.34mA   -50.8mA
-1.008V   -40.24mA   -47.71mA   -42.75mA
-962mV    -33.04mA   -36.52mA   -37.26mA
-916mV    -28.06mA   -28.96mA   -32.57mA
-847mV    -22.15mA   -21.6mA    -25.99mA
-755mV    -14.93mA   -14.48mA   -17.84mA
-640mV    -7mA       -7.443mA   -8.458mA
-548mV    -2.55mA    -3.36mA    -2.95mA
-456mV    -410.2uA   -964.6uA   -356.6uA
-341mV    -10.46uA   -82.06uA   -3.329uA
1.1V      0A         0A         0A
[POWER_clamp]
|Voltage   I(typ)   I(min)   I(max)
-1.085V   71.41mA    95.35mA    58.18mA
-1.062V   59.23mA    82.55mA    46.99mA
-1.039V   48.36mA    70.56mA    37.71mA
-1.016V   38.97mA    59.53mA    30.53mA
-970mV    25.17mA    40.76mA    21.88mA
-924mV    17.37mA    26.93mA    17.87mA
-901mV    15.03mA    21.86mA    16.59mA
-855mV    12.01mA    14.79mA    14.5mA
-763mV    8.448mA    8.108mA    10.89mA
-533mV    2.369mA    2.267mA    3.272mA
-349mV    143.9uA    291.4uA    171.3uA
1.1V      0A         0A         0A
[Ramp]
| variable   typ   min   max
dV/dt_r   76.557m/0.175n   78.807m/0.186n   66.720m/0.168n
dV/dt_f   0.119/0.153n   0.116/0.173n   0.115/0.143n
R_load = 50.000
[Rising Waveform]
R_fixture= 50.000
V_fixture= 0.0
V_fixture_min= 0.0
V_fixture_max= 0.0
|time   V(typ)   V(min)   V(max)
0s        2.271uV    12.08uV    1.02uV
391ps     280.3uV    140.9uV    415.4uV
494ps     1.3mV      -27.62uV   51.91mV
575ps     45.94mV    -524.5uV   81.42mV
686ps     94.43mV    53.92mV    99.43mV
749ps     107.9mV    83.45mV    104.1mV
829ps     117.2mV    105.9mV    107.4mV
985ps     124.5mV    123.7mV    110mV
1.205ns   126.9mV    129.7mV    110.9mV
10ns      127.6mV    131.4mV    111.2mV
[Rising Waveform]
R_fixture= 50.000
V_fixture= 0.550
V_fixture_min= 0.534
V_fixture_max= 0.568
|time   V(typ)   V(min)   V(max)
0s        450.6mV    436.2mV    471.2mV
397ps     450.8mV    436.4mV    472.4mV
496ps     457.2mV    436.2mV    554.9mV
568ps     516.1mV    438.4mV    593.2mV
611ps     549.3mV    454.8mV    606.4mV
655ps     572.9mV    491.7mV    615.5mV
778ps     605.4mV    564.7mV    627.7mV
886ps     615.4mV    588.9mV    631.5mV
1.03ns    620mV      600.2mV    633.3mV
10ns      622.6mV    605.9mV    634.5mV
[Falling Waveform]
R_fixture= 50.000
V_fixture= 0.550
V_fixture_min= 0.534
V_fixture_max= 0.568
|time   V(typ)   V(min)   V(max)
0s        622.6mV    605.9mV    634.5mV
383ps     622.5mV    605.8mV    634.8mV
487ps     618.7mV    606.3mV    538.8mV
563ps     542.1mV    605.2mV    503.1mV
594ps     518.1mV    592.4mV    494.9mV
638ps     494.8mV    551.6mV    486.9mV
743ps     467.6mV    481.1mV    477.3mV
843ps     457.9mV    455.4mV    474mV
974ps     453.4mV    443.1mV    472.4mV
10ns      450.6mV    436.2mV    471.2mV
[Falling Waveform]
R_fixture= 50.000
V_fixture= 0.0
V_fixture_min= 0.0
V_fixture_max= 0.0
|time   V(typ)   V(min)   V(max)
0s        127.6mV    131.4mV    111.2mV
384ps     127.7mV    131.3mV    111.6mV
481ps     126.3mV    132mV      50.54mV
556ps     73.69mV    131.4mV    23.96mV
637ps     32.66mV    87.77mV    11.25mV
695ps     19.07mV    49.97mV    6.697mV
765ps     10.28mV    26.1mV     3.68mV
887ps     3.745mV    9.304mV    1.458mV
1.117ns   815.4uV    1.75mV     460.6uV
10ns      2.281uV    12.08uV    1.045uV
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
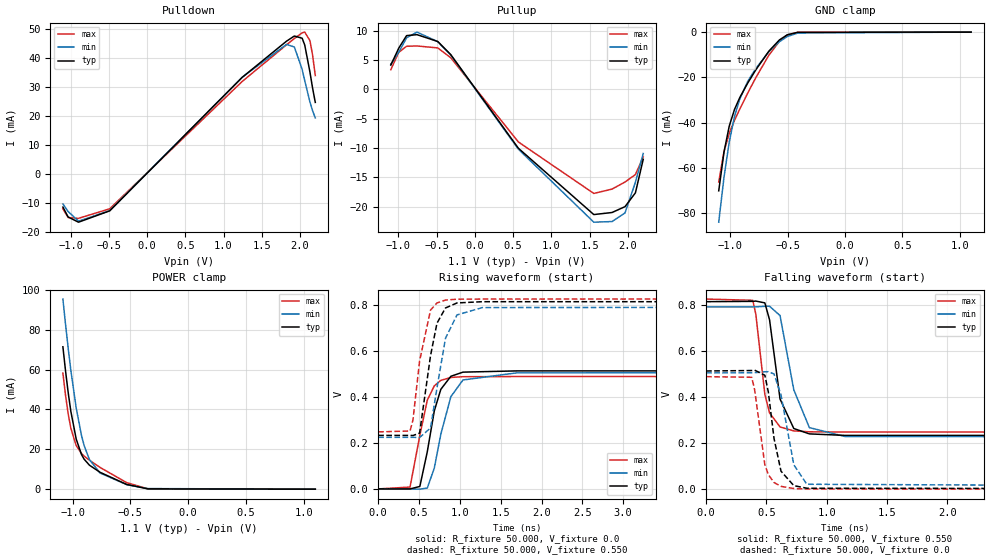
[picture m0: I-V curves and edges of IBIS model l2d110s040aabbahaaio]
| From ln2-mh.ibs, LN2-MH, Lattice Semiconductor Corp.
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|   Model l2d110s040aabbahaaio
[Model] l2d110s040aabbahaaio
| Clamp models do not include dynamic input termination. Please refer to
| the l2d110axxxaabbahaain model for input termination.
Model_type I/O
Polarity   Non-Inverting
Enable   Active-Low
Vinl =  0.200V
Vinh =  0.300V
Vmeas =  0.550V
Cref =  20.000pF
Rref =  50.000
Vref =  0.600V
C_comp   2.000pF   1.500pF   2.500pF
[Temperature Range]   25.000   0.125k   -40.000
[Voltage Range]   1.100V   1.070V   1.130V
[C Comp Corner]
C_comp   2.000pF   1.500pF   2.500pF
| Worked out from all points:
|   slope of the pulldown table from 0 to 0.165 V, typ, clamps not added: 36.9 ohm
|   slope of the pullup table from 0 to 0.165 V, typ, clamps not added: 52.6 ohm
|   GND clamp passes 1 mA (typ) near -0.49 V on its own axis
|   POWER clamp passes 1 mA (typ) near -0.45 V on its own axis
|   rising waveform, R_fixture 50.000, V_fixture 0.0: 20-80 % time 167ps typ, 200ps min, 155ps max; typ from 0 V to 0.515 V
|   rising waveform, R_fixture 50.000, V_fixture 0.550: 20-80 % time 137ps typ, 163ps min, 127ps max; typ from 0.233 V to 0.816 V
|   falling waveform, R_fixture 50.000, V_fixture 0.550: 20-80 % time 96.1ps typ, 125ps min, 83.6ps max; typ from 0.816 V to 0.233 V
|   falling waveform, R_fixture 50.000, V_fixture 0.0: 20-80 % time 86.7ps typ, 107ps min, 79.4ps max; typ from 0.515 V to 0 V
[Pulldown]
|Voltage   I(typ)   I(min)   I(max)
-1.1V     -11.54mA   -10.46mA   -12.1mA
-1.032V   -14.95mA   -13.05mA   -15.15mA
-896mV    -16.75mA   -16.38mA   -15.42mA
-488mV    -12.84mA   -12.77mA   -12.13mA
1.246V    33.22mA    33.26mA    31.81mA
1.824V    45.66mA    44.54mA    44.41mA
1.926V    47.43mA    43.65mA    46.57mA
2.028V    46.68mA    35.94mA    48.54mA
2.062V    44.32mA    32.03mA    48.79mA
2.13V     35mA       24.68mA    45.83mA
2.164V    29.56mA    21.75mA    40.94mA
2.2V      24.55mA    19.2mA     33.8mA
[Pullup]
|Voltage   I(typ)   I(min)   I(max)
-1.1V     4.135mA    4.293mA    3.355mA
-996mV    7.03mA     6.335mA    6.318mA
-894mV    9.159mA    8.78mA     7.344mA
-758mV    9.324mA    9.762mA    7.4mA
-486mV    8.157mA    8.129mA    7.064mA
-316mV    5.917mA    5.851mA    5.381mA
568mV     -10.04mA   -10.2mA    -8.966mA
1.554V    -21.34mA   -22.64mA   -17.74mA
1.792V    -20.99mA   -22.53mA   -17mA
1.962V    -19.99mA   -21.06mA   -15.79mA
2.098V    -17.64mA   -15.83mA   -14.52mA
2.2V      -11.93mA   -10.94mA   -11.52mA
[GND_clamp]
|Voltage   I(typ)   I(min)   I(max)
-1.1V     -70.17mA   -84.03mA   -66.28mA
-1.054V   -53mA      -64.11mA   -52.78mA
-1.008V   -41.48mA   -48.48mA   -44.68mA
-962mV    -34.13mA   -37.21mA   -38.95mA
-916mV    -28.9mA    -29.48mA   -33.97mA
-847mV    -22.51mA   -21.79mA   -26.94mA
-778mV    -16.78mA   -16.17mA   -20.25mA
-663mV    -8.429mA   -8.708mA   -10.22mA
-571mV    -3.466mA   -4.237mA   -4.093mA
-502mV    -1.18mA    -1.941mA   -1.256mA
-410mV    -105.5uA   -402.4uA   -63.37uA
1.1V      0A         0A         0A
[POWER_clamp]
|Voltage   I(typ)   I(min)   I(max)
-1.085V   71.41mA    95.35mA    58.18mA
-1.062V   59.23mA    82.55mA    46.99mA
-1.039V   48.36mA    70.56mA    37.71mA
-1.016V   38.97mA    59.53mA    30.53mA
-970mV    25.17mA    40.76mA    21.88mA
-924mV    17.37mA    26.93mA    17.87mA
-901mV    15.03mA    21.86mA    16.59mA
-855mV    12.01mA    14.79mA    14.5mA
-763mV    8.448mA    8.108mA    10.89mA
-533mV    2.369mA    2.267mA    3.272mA
-349mV    143.9uA    291.4uA    171.3uA
1.1V      0A         0A         0A
[Ramp]
| variable   typ   min   max
dV/dt_r   0.309/0.168n   0.304/0.200n   0.294/0.155n
dV/dt_f   0.379/0.107n   0.371/0.144n   0.381/88.702p
R_load = 50.000
[Rising Waveform]
R_fixture= 50.000
V_fixture= 0.0
V_fixture_min= 0.0
V_fixture_max= 0.0
|time   V(typ)   V(min)   V(max)
0s        1.068uV    5.74uV     488.6nV
390ps     -99.38uV   58.45uV    8.086mV
510ps     10.77mV    -1.089mV   233.3mV
601ps     161.5mV    3.597mV    386.6mV
687ps     340.3mV    90.73mV    449.3mV
767ps     434.3mV    238.6mV    473.3mV
890ps     491.1mV    402.2mV    485.9mV
1.038ns   509.2mV    475mV      489.3mV
1.7ns     514.6mV    506.2mV    490mV
10ns      514.6mV    506.5mV    490mV
[Rising Waveform]
R_fixture= 50.000
V_fixture= 0.550
V_fixture_min= 0.534
V_fixture_max= 0.568
|time   V(typ)   V(min)   V(max)
0s        233.5mV    224.9mV    248.7mV
390ps     233.4mV    225mV      252.5mV
426ps     232.8mV    225mV      301.1mV
507ps     243.3mV    224.2mV    558mV
641ps     581.3mV    265.7mV    779.9mV
720ps     722.7mV    441mV      810.8mV
824ps     788.9mV    656.9mV    823.5mV
965ps     810.9mV    758.7mV    827.2mV
1.275ns   816.3mV    790.7mV    827.8mV
10ns      816.5mV    793.4mV    827.8mV
[Falling Waveform]
R_fixture= 50.000
V_fixture= 0.550
V_fixture_min= 0.534
V_fixture_max= 0.568
|time   V(typ)   V(min)   V(max)
0s        816.4mV    793.4mV    827.8mV
387ps     817.8mV    793.5mV    822.4mV
412ps     819.1mV    793.9mV    762.4mV
487ps     811.1mV    796.2mV    412.8mV
526ps     737.5mV    796.6mV    332.1mV
613ps     392.4mV    755.9mV    270.9mV
727ps     264.1mV    432.6mV    253.7mV
856ps     240.7mV    268.1mV    249.8mV
1.151ns   234.1mV    229.3mV    248.7mV
10ns      233.5mV    224.9mV    248.7mV
[Falling Waveform]
R_fixture= 50.000
V_fixture= 0.0
V_fixture_min= 0.0
V_fixture_max= 0.0
|time   V(typ)   V(min)   V(max)
0s        514.6mV    506.5mV    489.9mV
378ps     516.6mV    506.7mV    487.2mV
402ps     518.3mV    507.1mV    433.9mV
487ps     496.1mV    511.2mV    106.4mV
516ps     422.8mV    511.5mV    63.03mV
563ps     221.1mV    501.6mV    29.02mV
621ps     78.29mV    410.7mV    12.16mV
727ps     15.5mV     106.2mV    2.865mV
835ps     4.012mV    21.34mV    727.4uV
10ns      1.067uV    5.73uV     492.6nV
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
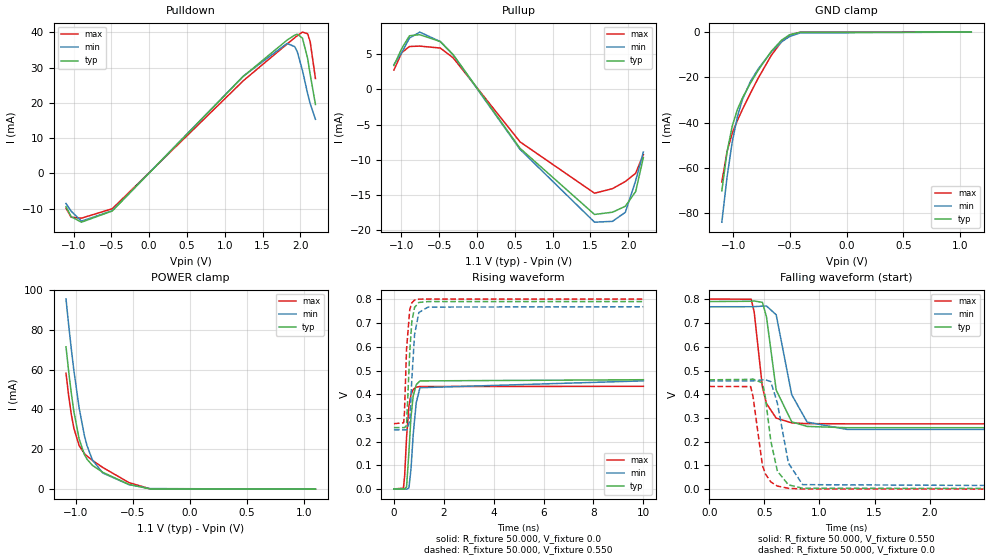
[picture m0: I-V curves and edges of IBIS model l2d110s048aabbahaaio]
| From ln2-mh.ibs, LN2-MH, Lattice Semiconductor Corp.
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|   Model l2d110s048aabbahaaio
[Model] l2d110s048aabbahaaio
| Clamp models do not include dynamic input termination. Please refer to
| the l2d110axxxaabbahaain model for input termination.
Model_type I/O
Polarity   Non-Inverting
Enable   Active-Low
Vinl =  0.200V
Vinh =  0.300V
Vmeas =  0.550V
Cref =  20.000pF
Rref =  50.000
Vref =  0.600V
C_comp   2.000pF   1.500pF   2.500pF
[Temperature Range]   25.000   0.125k   -40.000
[Voltage Range]   1.100V   1.070V   1.130V
[C Comp Corner]
C_comp   2.000pF   1.500pF   2.500pF
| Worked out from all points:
|   slope of the pulldown table from 0 to 0.165 V, typ, clamps not added: 44.4 ohm
|   slope of the pullup table from 0 to 0.165 V, typ, clamps not added: 63.1 ohm
|   GND clamp passes 1 mA (typ) near -0.49 V on its own axis
|   POWER clamp passes 1 mA (typ) near -0.45 V on its own axis
|   rising waveform, R_fixture 50.000, V_fixture 0.0: 20-80 % time 171ps typ, 207ps min, 153ps max; typ from 0 V to 0.461 V
|   rising waveform, R_fixture 50.000, V_fixture 0.550: 20-80 % time 141ps typ, 170ps min, 124ps max; typ from 0.259 V to 0.791 V
|   falling waveform, R_fixture 50.000, V_fixture 0.550: 20-80 % time 104ps typ, 137ps min, 86.9ps max; typ from 0.791 V to 0.259 V
|   falling waveform, R_fixture 50.000, V_fixture 0.0: 20-80 % time 91.7ps typ, 114ps min, 82.6ps max; typ from 0.461 V to 0 V
[Pulldown]
|Voltage   I(typ)   I(min)   I(max)
-1.1V     -9.41mA    -8.535mA   -9.849mA
-1.032V   -12.26mA   -10.69mA   -12.43mA
-896mV    -13.83mA   -13.52mA   -12.69mA
-488mV    -10.64mA   -10.58mA   -10.02mA
1.246V    27.54mA    27.59mA    26.3mA
1.824V    37.8mA     36.87mA    36.7mA
1.926V    39.24mA    35.96mA    38.49mA
1.96V     39.48mA    34.49mA    39.08mA
2.028V    38.4mA     29.21mA    40.09mA
2.096V    32.66mA    22.68mA    39.63mA
2.13V     28.15mA    19.83mA    37.42mA
2.2V      19.56mA    15.36mA    26.91mA
[Pullup]
|Voltage   I(typ)   I(min)   I(max)
-1.1V     3.391mA    3.517mA    2.749mA
-996mV    5.814mA    5.23mA     5.224mA
-894mV    7.622mA    7.298mA    6.097mA
-758mV    7.769mA    8.144mA    6.15mA
-486mV    6.803mA    6.791mA    5.876mA
-316mV    4.941mA    4.892mA    4.481mA
568mV     -8.372mA   -8.524mA   -7.458mA
1.554V    -17.78mA   -18.88mA   -14.76mA
1.792V    -17.46mA   -18.76mA   -14.11mA
1.962V    -16.61mA   -17.47mA   -13.09mA
2.098V    -14.53mA   -12.98mA   -11.92mA
2.2V      -9.694mA   -8.899mA   -9.266mA
[GND_clamp]
|Voltage   I(typ)   I(min)   I(max)
-1.1V     -70.17mA   -84.03mA   -66.26mA
-1.054V   -53mA      -64.11mA   -52.77mA
-1.008V   -41.47mA   -48.47mA   -44.67mA
-962mV    -34.12mA   -37.21mA   -38.94mA
-916mV    -28.89mA   -29.48mA   -33.96mA
-847mV    -22.51mA   -21.78mA   -26.94mA
-778mV    -16.78mA   -16.17mA   -20.25mA
-663mV    -8.428mA   -8.708mA   -10.22mA
-571mV    -3.466mA   -4.237mA   -4.093mA
-502mV    -1.18mA    -1.941mA   -1.256mA
-410mV    -105.5uA   -402.4uA   -63.37uA
1.1V      0A         0A         0A
[POWER_clamp]
|Voltage   I(typ)   I(min)   I(max)
-1.085V   71.41mA    95.35mA    58.18mA
-1.062V   59.23mA    82.55mA    46.99mA
-1.039V   48.36mA    70.56mA    37.71mA
-1.016V   38.97mA    59.53mA    30.53mA
-970mV    25.17mA    40.76mA    21.88mA
-924mV    17.37mA    26.93mA    17.87mA
-901mV    15.03mA    21.86mA    16.59mA
-855mV    12.01mA    14.79mA    14.5mA
-763mV    8.448mA    8.108mA    10.89mA
-533mV    2.369mA    2.267mA    3.272mA
-349mV    143.9uA    291.4uA    171.3uA
1.1V      0A         0A         0A
[Ramp]
| variable   typ   min   max
dV/dt_r   0.277/0.171n   0.274/0.207n   0.260/0.153n
dV/dt_f   0.349/0.117n   0.341/0.162n   0.349/92.180p
R_load = 50.000
[Rising Waveform]
R_fixture= 50.000
V_fixture= 0.0
V_fixture_min= 0.0
V_fixture_max= 0.0
|time   V(typ)   V(min)   V(max)
0s        1.208uV    6.471uV    552nV
382ps     14.42uV    58.31uV    3.143mV
430ps     -1.056mV   85.7uV     55.11mV
508ps     9.16mV     -1.042mV   220mV
602ps     156.7mV    4.063mV    349.1mV
684ps     304mV      83.41mV    397.9mV
773ps     392.7mV    229.4mV    419.7mV
895ps     440mV      364.3mV    429.7mV
1.044ns   456.1mV    427.4mV    432.6mV
10ns      461.1mV    456.3mV    433.1mV
[Rising Waveform]
R_fixture= 50.000
V_fixture= 0.550
V_fixture_min= 0.534
V_fixture_max= 0.568
|time   V(typ)   V(min)   V(max)
0s        258.9mV    249.5mV    275.5mV
390ps     258.8mV    249.5mV    279.1mV
422ps     258.3mV    249.6mV    321.3mV
507ps     268.5mV    248.8mV    591.6mV
636ps     581.2mV    286.4mV    758.3mV
719ps     707mV      464.7mV    786.1mV
828ps     766.3mV    651.9mV    797.7mV
1ns       787.4mV    744.9mV    801.3mV
1.369ns   791.2mV    767.9mV    801.7mV
10ns      791.2mV    769.2mV    801.7mV
[Falling Waveform]
R_fixture= 50.000
V_fixture= 0.550
V_fixture_min= 0.534
V_fixture_max= 0.568
|time   V(typ)   V(min)   V(max)
0s        791.2mV    769.2mV    801.6mV
380ps     792.3mV    769.3mV    801mV
407ps     793.5mV    769.6mV    747.3mV
482ps     787.8mV    771.7mV    429.5mV
519ps     725.9mV    772.4mV    360.8mV
607ps     417.8mV    735.2mV    299.6mV
748ps     283.8mV    398.1mV    279.5mV
888ps     264.6mV    282.8mV    276.3mV
1.246ns   259.2mV    252.2mV    275.5mV
10ns      258.9mV    249.5mV    275.5mV
[Falling Waveform]
R_fixture= 50.000
V_fixture= 0.0
V_fixture_min= 0.0
V_fixture_max= 0.0
|time   V(typ)   V(min)   V(max)
0s        461mV      456.3mV    433.1mV
375ps     462.9mV    456.4mV    432.5mV
396ps     464.3mV    456.8mV    392.5mV
482ps     447.7mV    460.7mV    100.1mV
509ps     386.7mV    461.3mV    64.31mV
558ps     203mV      453.5mV    30.42mV
618ps     75.88mV    362mV      13.14mV
718ps     18.28mV    109.8mV    3.591mV
847ps     3.935mV    19.07mV    757.5uV
10ns      1.208uV    6.463uV    557.1nV
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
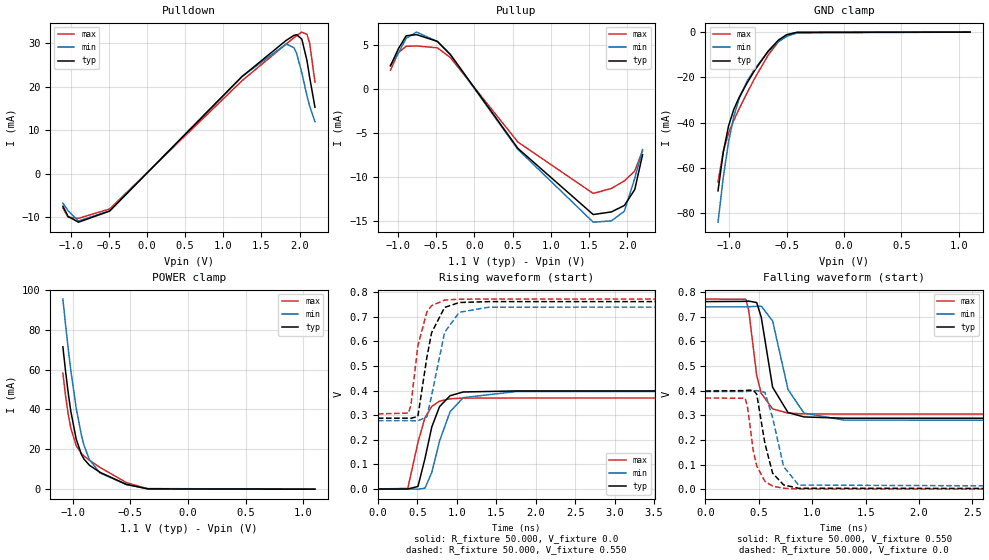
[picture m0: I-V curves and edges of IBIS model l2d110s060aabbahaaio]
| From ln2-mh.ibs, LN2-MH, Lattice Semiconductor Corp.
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|   Model l2d110s060aabbahaaio
[Model] l2d110s060aabbahaaio
| Clamp models do not include dynamic input termination. Please refer to
| the l2d110axxxaabbahaain model for input termination.
Model_type I/O
Polarity   Non-Inverting
Enable   Active-Low
Vinl =  0.200V
Vinh =  0.300V
Vmeas =  0.550V
Cref =  20.000pF
Rref =  50.000
Vref =  0.600V
C_comp   2.000pF   1.500pF   2.500pF
[Temperature Range]   25.000   0.125k   -40.000
[Voltage Range]   1.100V   1.070V   1.130V
[C Comp Corner]
C_comp   2.000pF   1.500pF   2.500pF
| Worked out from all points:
|   slope of the pulldown table from 0 to 0.165 V, typ, clamps not added: 54.8 ohm
|   slope of the pullup table from 0 to 0.165 V, typ, clamps not added: 78.5 ohm
|   GND clamp passes 1 mA (typ) near -0.49 V on its own axis
|   POWER clamp passes 1 mA (typ) near -0.45 V on its own axis
|   rising waveform, R_fixture 50.000, V_fixture 0.0: 20-80 % time 185ps typ, 228ps min, 162ps max; typ from 0 V to 0.398 V
|   rising waveform, R_fixture 50.000, V_fixture 0.550: 20-80 % time 150ps typ, 183ps min, 132ps max; typ from 0.288 V to 0.762 V
|   falling waveform, R_fixture 50.000, V_fixture 0.550: 20-80 % time 117ps typ, 156ps min, 96.9ps max; typ from 0.762 V to 0.288 V
|   falling waveform, R_fixture 50.000, V_fixture 0.0: 20-80 % time 102ps typ, 127ps min, 90.8ps max; typ from 0.398 V to 0 V
[Pulldown]
|Voltage   I(typ)   I(min)   I(max)
-1.1V     -7.499mA   -6.787mA   -7.895mA
-1.032V   -9.836mA   -8.546mA   -10.04mA
-896mV    -11.17mA   -10.89mA   -10.28mA
-488mV    -8.614mA   -8.561mA   -8.134mA
1.246V    22.32mA    22.34mA    21.37mA
1.824V    30.63mA    29.8mA     29.8mA
1.926V    31.78mA    28.92mA    31.25mA
1.96V     31.94mA    27.63mA    31.73mA
2.028V    30.91mA    23.16mA    32.53mA
2.096V    25.92mA    17.81mA    32mA
2.13V     22.15mA    15.51mA    29.99mA
2.2V      15.25mA    11.94mA    21.05mA
[Pullup]
|Voltage   I(typ)   I(min)   I(max)
-1.1V     2.659mA    2.739mA    2.174mA
-996mV    4.615mA    4.123mA    4.178mA
-894mV    6.091mA    5.806mA    4.892mA
-758mV    6.217mA    6.508mA    4.932mA
-486mV    5.452mA    5.436mA    4.716mA
-316mV    3.967mA    3.921mA    3.605mA
568mV     -6.721mA   -6.835mA   -6mA
1.554V    -14.25mA   -15.12mA   -11.85mA
1.792V    -13.95mA   -14.97mA   -11.28mA
1.962V    -13.22mA   -13.87mA   -10.42mA
2.098V    -11.41mA   -10.13mA   -9.293mA
2.2V      -7.455mA   -6.863mA   -6.994mA
[GND_clamp]
|Voltage   I(typ)   I(min)   I(max)
-1.1V     -70.16mA   -84.02mA   -66.23mA
-1.054V   -52.99mA   -64.1mA    -52.74mA
-1.008V   -41.46mA   -48.47mA   -44.65mA
-962mV    -34.12mA   -37.21mA   -38.93mA
-916mV    -28.89mA   -29.48mA   -33.95mA
-847mV    -22.5mA    -21.78mA   -26.93mA
-778mV    -16.78mA   -16.17mA   -20.24mA
-663mV    -8.428mA   -8.707mA   -10.21mA
-571mV    -3.466mA   -4.237mA   -4.093mA
-502mV    -1.179mA   -1.94mA    -1.256mA
-410mV    -105.5uA   -402.4uA   -63.37uA
1.1V      0A         0A         0A
[POWER_clamp]
|Voltage   I(typ)   I(min)   I(max)
-1.085V   71.41mA    95.35mA    58.18mA
-1.062V   59.23mA    82.55mA    46.99mA
-1.039V   48.36mA    70.56mA    37.71mA
-1.016V   38.97mA    59.53mA    30.53mA
-970mV    25.17mA    40.76mA    21.88mA
-924mV    17.37mA    26.93mA    17.87mA
-901mV    15.03mA    21.86mA    16.59mA
-855mV    12.01mA    14.79mA    14.5mA
-763mV    8.448mA    8.108mA    10.89mA
-533mV    2.369mA    2.267mA    3.272mA
-349mV    143.9uA    291.4uA    171.3uA
1.1V      0A         0A         0A
[Ramp]
| variable   typ   min   max
dV/dt_r   0.239/0.185n   0.238/0.228n   0.222/0.162n
dV/dt_f   0.314/0.132n   0.307/0.184n   0.314/0.103n
R_load = 50.000
[Rising Waveform]
R_fixture= 50.000
V_fixture= 0.0
V_fixture_min= 0.0
V_fixture_max= 0.0
|time   V(typ)   V(min)   V(max)
0s        1.37uV     7.322uV    623.3nV
379ps     35.53uV    62.25uV    2.294mV
508ps     10.14mV    -806.5uV   189.2mV
597ps     124mV      3.345mV    290.2mV
683ps     251.8mV    67.38mV    335.6mV
781ps     334.7mV    194.8mV    357mV
915ps     379.1mV    313.9mV    366.6mV
1.081ns   394.2mV    371.1mV    369.3mV
1.756ns   398.5mV    396.2mV    369.8mV
10ns      398.5mV    396.5mV    369.8mV
[Rising Waveform]
R_fixture= 50.000
V_fixture= 0.550
V_fixture_min= 0.534
V_fixture_max= 0.568
|time   V(typ)   V(min)   V(max)
0s        287.8mV    277.7mV    304.9mV
390ps     287.7mV    277.7mV    308.6mV
420ps     287.3mV    277.7mV    344.6mV
507ps     294.9mV    277.2mV    582.8mV
621ps     535.3mV    292.8mV    719.4mV
681ps     635.3mV    380mV      745.2mV
845ps     737.9mV    636.3mV    767.8mV
1.031ns   757.9mV    718mV      771.4mV
1.404ns   761.5mV    738.8mV    771.9mV
10ns      761.5mV    740.2mV    771.8mV
[Falling Waveform]
R_fixture= 50.000
V_fixture= 0.550
V_fixture_min= 0.534
V_fixture_max= 0.568
|time   V(typ)   V(min)   V(max)
0s        761.5mV    740.2mV    771.8mV
378ps     762.5mV    740.2mV    770.9mV
405ps     763.6mV    740.5mV    726.8mV
480ps     757.6mV    742.4mV    461mV
523ps     697.4mV    742.6mV    388.9mV
629ps     413.8mV    683mV      325.9mV
773ps     311.1mV    405.3mV    308.8mV
922ps     293.3mV    308.9mV    305.7mV
1.298ns   288mV      280.3mV    304.9mV
10ns      287.8mV    277.6mV    304.9mV
[Falling Waveform]
R_fixture= 50.000
V_fixture= 0.0
V_fixture_min= 0.0
V_fixture_max= 0.0
|time   V(typ)   V(min)   V(max)
0s        398.5mV    396.5mV    369.8mV
373ps     400.1mV    396.5mV    369.3mV
395ps     401.5mV    396.9mV    330.8mV
448ps     402.3mV    398.7mV    155.7mV
480ps     385.7mV    400.3mV    94.5mV
557ps     185.7mV    393mV      31.44mV
629ps     64.97mV    290.2mV    12.42mV
732ps     17.3mV     91.67mV    3.645mV
872ps     3.725mV    16.67mV    810.3uV
10ns      1.372uV    7.318uV    630.3nV
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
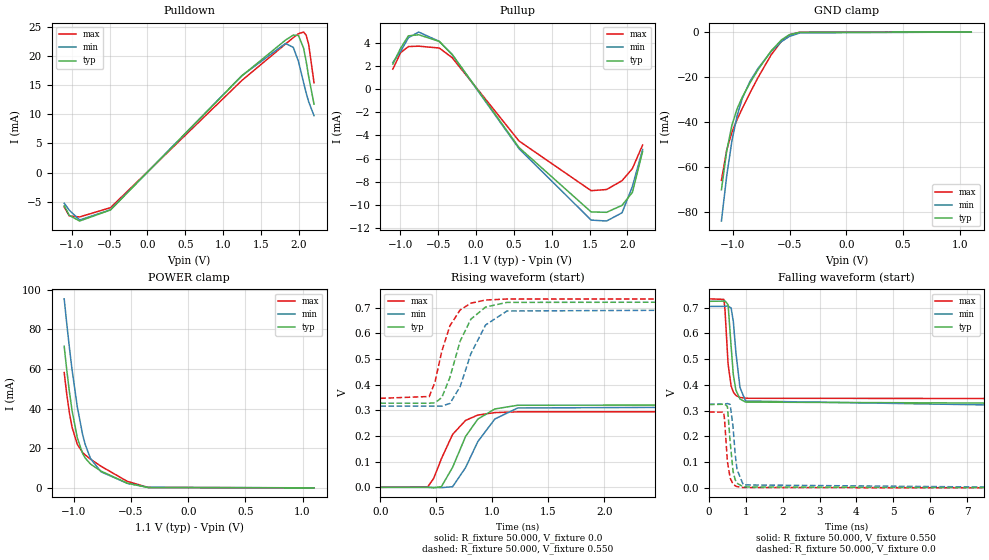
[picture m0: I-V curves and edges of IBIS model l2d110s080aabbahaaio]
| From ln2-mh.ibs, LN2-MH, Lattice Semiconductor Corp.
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|   Model l2d110s080aabbahaaio
[Model] l2d110s080aabbahaaio
| Clamp models do not include dynamic input termination. Please refer to
| the l2d110axxxaabbahaain model for input termination.
Model_type I/O
Polarity   Non-Inverting
Enable   Active-Low
Vinl =  0.200V
Vinh =  0.300V
Vmeas =  0.550V
Cref =  20.000pF
Rref =  50.000
Vref =  0.600V
C_comp   2.000pF   1.500pF   2.500pF
[Temperature Range]   25.000   0.125k   -40.000
[Voltage Range]   1.100V   1.070V   1.130V
[C Comp Corner]
C_comp   2.000pF   1.500pF   2.500pF
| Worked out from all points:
|   slope of the pulldown table from 0 to 0.165 V, typ, clamps not added: 73.8 ohm
|   slope of the pullup table from 0 to 0.165 V, typ, clamps not added: 104 ohm
|   GND clamp passes 1 mA (typ) near -0.49 V on its own axis
|   POWER clamp passes 1 mA (typ) near -0.45 V on its own axis
|   rising waveform, R_fixture 50.000, V_fixture 0.0: 20-80 % time 222ps typ, 258ps min, 195ps max; typ from 0 V to 0.324 V
|   rising waveform, R_fixture 50.000, V_fixture 0.550: 20-80 % time 185ps typ, 216ps min, 156ps max; typ from 0.328 V to 0.725 V
|   falling waveform, R_fixture 50.000, V_fixture 0.550: 20-80 % time 130ps typ, 162ps min, 114ps max; typ from 0.725 V to 0.328 V
|   falling waveform, R_fixture 50.000, V_fixture 0.0: 20-80 % time 113ps typ, 128ps min, 105ps max; typ from 0.324 V to 0 V
[Pulldown]
|Voltage   I(typ)   I(min)   I(max)
-1.1V     -5.675mA   -5.241mA   -5.881mA
-1.032V   -7.334mA   -6.457mA   -7.433mA
-896mV    -8.3mA     -8.119mA   -7.6mA
-488mV    -6.4mA     -6.37mA    -6.008mA
1.246V    16.59mA    16.63mA    15.8mA
1.824V    22.74mA    22.16mA    22.07mA
1.926V    23.59mA    21.49mA    23.15mA
1.994V    23.53mA    19.11mA    23.83mA
2.062V    21.38mA    15.45mA    24.12mA
2.096V    19.11mA    13.68mA    23.59mA
2.13V     16.44mA    12.14mA    21.98mA
2.2V      11.76mA    9.772mA    15.43mA
[Pullup]
|Voltage   I(typ)   I(min)   I(max)
-1.1V     2.15mA     2.287mA    1.709mA
-996mV    3.524mA    3.244mA    3.134mA
-894mV    4.58mA     4.417mA    3.654mA
-758mV    4.67mA     4.905mA    3.687mA
-486mV    4.097mA    4.096mA    3.528mA
-316mV    2.982mA    2.956mA    2.698mA
568mV     -5.048mA   -5.147mA   -4.484mA
1.52V     -10.59mA   -11.29mA   -8.759mA
1.724V    -10.62mA   -11.37mA   -8.658mA
1.928V    -10.02mA   -10.66mA   -7.895mA
2.064V    -8.913mA   -8.407mA   -6.86mA
2.2V      -5.376mA   -5.209mA   -4.823mA
[GND_clamp]
|Voltage   I(typ)   I(min)   I(max)
-1.1V     -70.14mA   -84.01mA   -65.93mA
-1.054V   -52.97mA   -64.09mA   -52.57mA
-1.008V   -41.45mA   -48.46mA   -44.57mA
-962mV    -34.1mA    -37.2mA    -38.89mA
-916mV    -28.88mA   -29.47mA   -33.93mA
-847mV    -22.5mA    -21.78mA   -26.92mA
-778mV    -16.77mA   -16.16mA   -20.24mA
-663mV    -8.426mA   -8.706mA   -10.21mA
-571mV    -3.465mA   -4.236mA   -4.092mA
-502mV    -1.179mA   -1.94mA    -1.256mA
-410mV    -105.5uA   -402.4uA   -63.37uA
1.1V      0A         0A         0A
[POWER_clamp]
|Voltage   I(typ)   I(min)   I(max)
-1.085V   71.41mA    95.35mA    58.18mA
-1.062V   59.23mA    82.55mA    46.99mA
-1.039V   48.36mA    70.56mA    37.71mA
-1.016V   38.97mA    59.53mA    30.53mA
-970mV    25.17mA    40.76mA    21.88mA
-924mV    17.37mA    26.93mA    17.87mA
-901mV    15.03mA    21.86mA    16.59mA
-855mV    12.01mA    14.79mA    14.5mA
-763mV    8.448mA    8.108mA    10.89mA
-533mV    2.369mA    2.267mA    3.272mA
-349mV    143.9uA    291.4uA    171.3uA
1.1V      0A         0A         0A
[Ramp]
| variable   typ   min   max
dV/dt_r   0.194/0.222n   0.195/0.258n   0.177/0.194n
dV/dt_f   0.266/0.145n   0.261/0.187n   0.264/0.125n
R_load = 50.000
[Rising Waveform]
R_fixture= 50.000
V_fixture= 0.0
V_fixture_min= 0.0
V_fixture_max= 0.0
|time   V(typ)   V(min)   V(max)
0s        1.59uV     8.481uV    722.6nV
423ps     -239.7uV   197.1uV    1.759mV
476ps     -1.985mV   32.04uV    34.81mV
545ps     2.674mV    -1.321mV   111.6mV
645ps     78.08mV    2.522mV    206.3mV
761ps     198.4mV    77.2mV     261mV
870ps     265.9mV    178.3mV    281.6mV
1.022ns   305.4mV    266.4mV    291.3mV
1.226ns   319.9mV    309.2mV    294.2mV
10ns      323.6mV    325mV      294.6mV
[Rising Waveform]
R_fixture= 50.000
V_fixture= 0.550
V_fixture_min= 0.534
V_fixture_max= 0.568
|time   V(typ)   V(min)   V(max)
0s        328mV      316.5mV    346.8mV
437ps     327.7mV    316.7mV    354mV
487ps     329.3mV    316.4mV    408.8mV
548ps     349.6mV    316.6mV    529.3mV
621ps     428.3mV    327mV      629.7mV
712ps     569.6mV    392.1mV    691.1mV
808ps     655.3mV    520.6mV    717.6mV
939ps     702.5mV    632.5mV    729.9mV
1.13ns    720.7mV    687.1mV    733.8mV
10ns      724.9mV    705.1mV    734.4mV
[Falling Waveform]
R_fixture= 50.000
V_fixture= 0.550
V_fixture_min= 0.534
V_fixture_max= 0.568
|time   V(typ)   V(min)   V(max)
0s        724.9mV    705.1mV    734.4mV
405ps     725.6mV    705.2mV    732.5mV
434ps     726.5mV    705.4mV    694.7mV
519ps     712mV      706.9mV    481.5mV
602ps     548.8mV    698.6mV    395.8mV
661ps     440.2mV    647.2mV    372.2mV
731ps     379.5mV    526.4mV    359.3mV
842ps     345.5mV    390mV      351.3mV
993ps     333.2mV    337.5mV    348.1mV
10ns      328mV      316.5mV    346.8mV
[Falling Waveform]
R_fixture= 50.000
V_fixture= 0.0
V_fixture_min= 0.0
V_fixture_max= 0.0
|time   V(typ)   V(min)   V(max)
0s        323.6mV    325mV      294.6mV
399ps     324.9mV    325.1mV    294.2mV
422ps     325.8mV    325.4mV    267.5mV
501ps     316.4mV    327.7mV    101.8mV
577ps     176.4mV    323.7mV    37.53mV
654ps     64.38mV    236.7mV    15.15mV
711ps     31.93mV    131.8mV    8.148mV
761ps     18.18mV    71.83mV    4.89mV
932ps     3.515mV    11.44mV    1.12mV
10ns      1.591uV    8.473uV    731.4nV
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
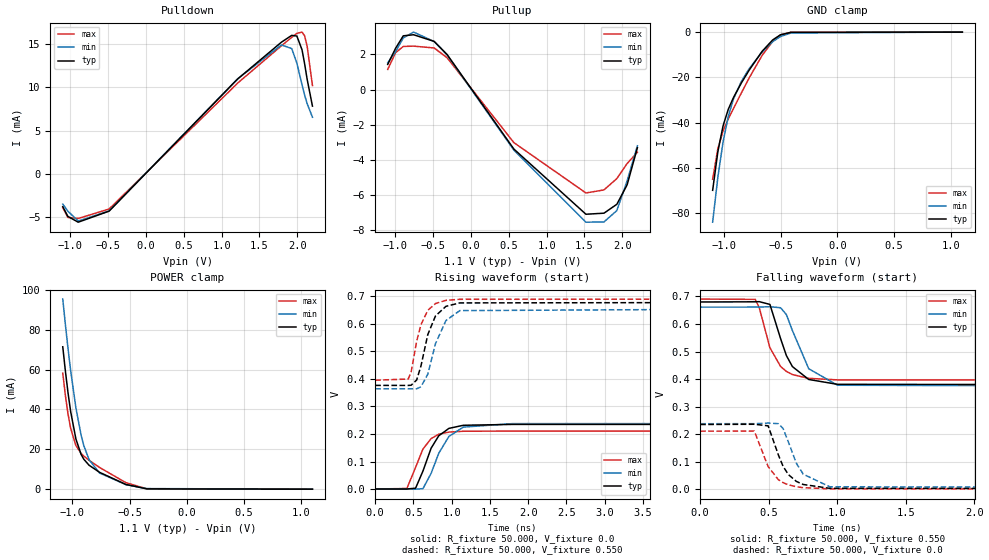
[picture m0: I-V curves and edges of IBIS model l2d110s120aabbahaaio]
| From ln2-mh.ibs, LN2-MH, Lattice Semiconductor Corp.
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|   Model l2d110s120aabbahaaio
[Model] l2d110s120aabbahaaio
| Clamp models do not include dynamic input termination. Please refer to
| the l2d110axxxaabbahaain model for input termination.
Model_type I/O
Polarity   Non-Inverting
Enable   Active-Low
Vinl =  0.200V
Vinh =  0.300V
Vmeas =  0.550V
Cref =  20.000pF
Rref =  50.000
Vref =  0.600V
C_comp   2.000pF   1.500pF   2.500pF
[Temperature Range]   25.000   0.125k   -40.000
[Voltage Range]   1.100V   1.070V   1.130V
[C Comp Corner]
C_comp   2.000pF   1.500pF   2.500pF
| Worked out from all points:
|   slope of the pulldown table from 0 to 0.165 V, typ, clamps not added: 108 ohm
|   slope of the pullup table from 0 to 0.165 V, typ, clamps not added: 156 ohm
|   GND clamp passes 1 mA (typ) near -0.49 V on its own axis
|   POWER clamp passes 1 mA (typ) near -0.45 V on its own axis
|   rising waveform, R_fixture 50.000, V_fixture 0.0: 20-80 % time 212ps typ, 243ps min, 195ps max; typ from 0 V to 0.235 V
|   rising waveform, R_fixture 50.000, V_fixture 0.550: 20-80 % time 177ps typ, 204ps min, 158ps max; typ from 0.377 V to 0.68 V
|   falling waveform, R_fixture 50.000, V_fixture 0.550: 20-80 % time 137ps typ, 160ps min, 126ps max; typ from 0.68 V to 0.377 V
|   falling waveform, R_fixture 50.000, V_fixture 0.0: 20-80 % time 123ps typ, 134ps min, 119ps max; typ from 0.235 V to 0 V
[Pulldown]
|Voltage   I(typ)   I(min)   I(max)
-1.1V     -3.828mA   -3.534mA   -3.948mA
-1.032V   -4.961mA   -4.354mA   -5.077mA
-896mV    -5.627mA   -5.495mA   -5.197mA
-488mV    -4.347mA   -4.322mA   -4.101mA
1.212V    10.98mA    11mA       10.5mA
1.79V     15.24mA    14.92mA    14.82mA
1.926V    16.03mA    14.5mA     15.8mA
1.994V    15.95mA    12.81mA    16.26mA
2.062V    14.36mA    10.31mA    16.41mA
2.096V    12.76mA    9.126mA    15.99mA
2.13V     10.93mA    8.106mA    14.77mA
2.2V      7.825mA    6.542mA    10.21mA
[Pullup]
|Voltage   I(typ)   I(min)   I(max)
-1.1V     1.431mA    1.519mA    1.144mA
-996mV    2.344mA    2.153mA    2.098mA
-894mV    3.054mA    2.935mA    2.449mA
-758mV    3.115mA    3.266mA    2.469mA
-486mV    2.737mA    2.731mA    2.364mA
-316mV    1.997mA    1.974mA    1.813mA
568mV     -3.38mA    -3.44mA    -3.014mA
1.52V     -7.081mA   -7.532mA   -5.872mA
1.758V    -7.02mA    -7.517mA   -5.699mA
1.928V    -6.516mA   -6.874mA   -5.056mA
2.064V    -5.413mA   -5.187mA   -4.203mA
2.2V      -3.301mA   -3.193mA   -3.558mA
[GND_clamp]
|Voltage   I(typ)   I(min)   I(max)
-1.1V     -69.86mA   -83.93mA   -64.98mA
-1.054V   -52.78mA   -64.04mA   -51.45mA
-1.008V   -41.35mA   -48.42mA   -43.59mA
-962mV    -34.05mA   -37.17mA   -38.31mA
-916mV    -28.85mA   -29.45mA   -33.73mA
-847mV    -22.48mA   -21.76mA   -26.88mA
-778mV    -16.77mA   -16.16mA   -20.22mA
-663mV    -8.423mA   -8.703mA   -10.21mA
-571mV    -3.464mA   -4.235mA   -4.09mA
-502mV    -1.179mA   -1.94mA    -1.256mA
-410mV    -105.5uA   -402.4uA   -63.37uA
1.1V      0A         0A         0A
[POWER_clamp]
|Voltage   I(typ)   I(min)   I(max)
-1.085V   71.41mA    95.35mA    58.18mA
-1.062V   59.23mA    82.55mA    46.99mA
-1.039V   48.36mA    70.56mA    37.71mA
-1.016V   38.97mA    59.53mA    30.53mA
-970mV    25.17mA    40.76mA    21.88mA
-924mV    17.37mA    26.93mA    17.87mA
-901mV    15.03mA    21.86mA    16.59mA
-855mV    12.01mA    14.79mA    14.5mA
-763mV    8.448mA    8.108mA    10.89mA
-533mV    2.369mA    2.267mA    3.272mA
-349mV    143.9uA    291.4uA    171.3uA
1.1V      0A         0A         0A
[Ramp]
| variable   typ   min   max
dV/dt_r   0.141/0.212n   0.143/0.242n   0.126/0.194n
dV/dt_f   0.207/0.152n   0.203/0.186n   0.205/0.136n
R_load = 50.000
[Rising Waveform]
R_fixture= 50.000
V_fixture= 0.0
V_fixture_min= 0.0
V_fixture_max= 0.0
|time   V(typ)   V(min)   V(max)
0s        1.863uV    9.921uV    840.8nV
414ps     3.219uV    180uV      1.914mV
528ps     3.101mV    -574.5uV   78.72mV
624ps     65.04mV    1.347mV    145mV
731ps     148.4mV    57.01mV    183.3mV
831ps     193.6mV    130mV      199.1mV
964ps     220.4mV    191.3mV    207mV
1.152ns   231.7mV    225mV      210mV
1.796ns   234.9mV    237.8mV    210.7mV
10ns      234.9mV    237.8mV    210.7mV
[Rising Waveform]
R_fixture= 50.000
V_fixture= 0.550
V_fixture_min= 0.534
V_fixture_max= 0.568
|time   V(typ)   V(min)   V(max)
0s        376.7mV    364.2mV    395.6mV
431ps     376.6mV    364.4mV    399.8mV
470ps     377.3mV    364.3mV    425.8mV
542ps     396.4mV    364.4mV    537.3mV
598ps     447.1mV    371.6mV    597.5mV
688ps     561.9mV    417.7mV    649.9mV
788ps     629.1mV    528.3mV    674.3mV
925ps     664.2mV    612.7mV    686mV
1.106ns   676.6mV    648.6mV    689.8mV
10ns      680mV      661.3mV    690.6mV
[Falling Waveform]
R_fixture= 50.000
V_fixture= 0.550
V_fixture_min= 0.534
V_fixture_max= 0.568
|time   V(typ)   V(min)   V(max)
0s        680mV      661.3mV    690.6mV
402ps     680.6mV    661.4mV    689.4mV
431ps     681.2mV    661.5mV    659.6mV
509ps     671.2mV    662.8mV    513.6mV
587ps     546.6mV    659mV      445.6mV
629ps     485.5mV    634.2mV    427.8mV
673ps     445.3mV    576.4mV    416.3mV
792ps     398.5mV    437.5mV    402.6mV
1.002ns   380.8mV    377.6mV    397mV
10ns      376.7mV    364.2mV    395.6mV
[Falling Waveform]
R_fixture= 50.000
V_fixture= 0.0
V_fixture_min= 0.0
V_fixture_max= 0.0
|time   V(typ)   V(min)   V(max)
0s        234.9mV    237.8mV    210.7mV
395ps     235.8mV    237.9mV    211.1mV
496ps     230.1mV    240.1mV    81.94mV
571ps     123.9mV    237.9mV    34.32mV
605ps     82.88mV    220.3mV    23.68mV
644ps     52.89mV    171.1mV    15.71mV
702ps     28.21mV    93.98mV    8.777mV
752ps     16.99mV    54.34mV    5.431mV
946ps     3.018mV    8.609mV    1.158mV
10ns      1.866uV    9.918uV    852.8nV
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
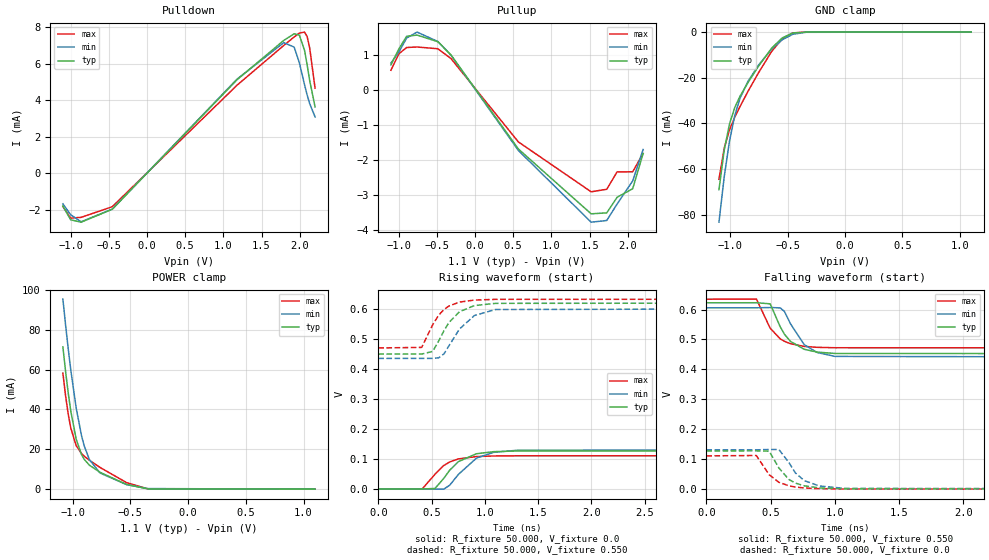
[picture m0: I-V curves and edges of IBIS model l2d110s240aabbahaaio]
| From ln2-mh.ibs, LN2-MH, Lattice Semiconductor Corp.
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|   Model l2d110s240aabbahaaio
[Model] l2d110s240aabbahaaio
| Clamp models do not include dynamic input termination. Please refer to
| the l2d110axxxaabbahaain model for input termination.
Model_type I/O
Polarity   Non-Inverting
Enable   Active-Low
Vinl =  0.200V
Vinh =  0.300V
Vmeas =  0.550V
Cref =  20.000pF
Rref =  50.000
Vref =  0.600V
C_comp   2.000pF   1.500pF   2.500pF
[Temperature Range]   25.000   0.125k   -40.000
[Voltage Range]   1.100V   1.070V   1.130V
[C Comp Corner]
C_comp   2.000pF   1.500pF   2.500pF
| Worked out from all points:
|   slope of the pulldown table from 0 to 0.165 V, typ, clamps not added: 226 ohm
|   slope of the pullup table from 0 to 0.165 V, typ, clamps not added: 313 ohm
|   GND clamp passes 1 mA (typ) near -0.49 V on its own axis
|   POWER clamp passes 1 mA (typ) near -0.45 V on its own axis
|   rising waveform, R_fixture 50.000, V_fixture 0.0: 20-80 % time 203ps typ, 228ps min, 185ps max; typ from 0 V to 0.128 V
|   rising waveform, R_fixture 50.000, V_fixture 0.550: 20-80 % time 193ps typ, 218ps min, 170ps max; typ from 0.451 V to 0.623 V
|   falling waveform, R_fixture 50.000, V_fixture 0.550: 20-80 % time 147ps typ, 165ps min, 139ps max; typ from 0.623 V to 0.451 V
|   falling waveform, R_fixture 50.000, V_fixture 0.0: 20-80 % time 141ps typ, 149ps min, 136ps max; typ from 0.128 V to 0 V
[Pulldown]
|Voltage   I(typ)   I(min)   I(max)
-1.1V     -1.799mA   -1.677mA   -1.823mA
-998mV    -2.552mA   -2.276mA   -2.459mA
-862mV    -2.684mA   -2.662mA   -2.419mA
-454mV    -1.973mA   -1.972mA   -1.836mA
1.178V    5.12mA     5.154mA    4.82mA
1.79V     7.277mA    7.157mA    7.001mA
1.926V    7.641mA    6.913mA    7.467mA
1.994V    7.572mA    6.061mA    7.683mA
2.062V    6.74mA     4.852mA    7.735mA
2.096V    5.944mA    4.292mA    7.494mA
2.13V     5.072mA    3.814mA    6.855mA
2.2V      3.635mA    3.086mA    4.66mA
[Pullup]
|Voltage   I(typ)   I(min)   I(max)
-1.1V     709.3uA    760.2uA    557.1uA
-996mV    1.163mA    1.077mA    1.025mA
-894mV    1.523mA    1.472mA    1.204mA
-758mV    1.557mA    1.642mA    1.218mA
-486mV    1.368mA    1.374mA    1.168mA
-316mV    997.2uA    993.3uA    894.4uA
568mV     -1.684mA   -1.725mA   -1.482mA
1.52V     -3.527mA   -3.765mA   -2.9mA
1.724V    -3.5mA     -3.717mA   -2.829mA
1.86V     -3.057mA   -3.248mA   -2.334mA
2.064V    -2.812mA   -2.59mA    -2.331mA
2.2V      -1.812mA   -1.697mA   -1.811mA
[GND_clamp]
|Voltage   I(typ)   I(min)   I(max)
-1.1V     -69.04mA   -83.29mA   -64.5mA
-1.054V   -51.76mA   -63.34mA   -50.8mA
-1.008V   -40.24mA   -47.71mA   -42.75mA
-962mV    -33.04mA   -36.52mA   -37.26mA
-916mV    -28.06mA   -28.96mA   -32.57mA
-847mV    -22.15mA   -21.6mA    -25.99mA
-755mV    -14.93mA   -14.48mA   -17.84mA
-640mV    -7mA       -7.443mA   -8.458mA
-548mV    -2.55mA    -3.36mA    -2.95mA
-456mV    -410.2uA   -964.6uA   -356.6uA
-341mV    -10.46uA   -82.06uA   -3.329uA
1.1V      0A         0A         0A
[POWER_clamp]
|Voltage   I(typ)   I(min)   I(max)
-1.085V   71.41mA    95.35mA    58.18mA
-1.062V   59.23mA    82.55mA    46.99mA
-1.039V   48.36mA    70.56mA    37.71mA
-1.016V   38.97mA    59.53mA    30.53mA
-970mV    25.17mA    40.76mA    21.88mA
-924mV    17.37mA    26.93mA    17.87mA
-901mV    15.03mA    21.86mA    16.59mA
-855mV    12.01mA    14.79mA    14.5mA
-763mV    8.448mA    8.108mA    10.89mA
-533mV    2.369mA    2.267mA    3.272mA
-349mV    143.9uA    291.4uA    171.3uA
1.1V      0A         0A         0A
[Ramp]
| variable   typ   min   max
dV/dt_r   76.557m/0.203n   78.807m/0.227n   66.720m/0.185n
dV/dt_f   0.119/0.159n   0.116/0.186n   0.115/0.145n
R_load = 50.000
[Rising Waveform]
R_fixture= 50.000
V_fixture= 0.0
V_fixture_min= 0.0
V_fixture_max= 0.0
|time   V(typ)   V(min)   V(max)
0s        2.271uV    12.08uV    1.02uV
412ps     76.5uV     194.4uV    196.3uV
532ps     1.717mV    -595.9uV   49.18mV
614ps     35.36mV    -551.9uV   78.35mV
670ps     62.64mV    12.59mV    90.33mV
752ps     91.52mV    48.74mV    100.5mV
922ps     117.8mV    103.4mV    108.4mV
1.082ns   124.7mV    122.3mV    110.3mV
1.302ns   127mV      129.4mV    110.9mV
10ns      127.6mV    131.4mV    111.2mV
[Rising Waveform]
R_fixture= 50.000
V_fixture= 0.550
V_fixture_min= 0.534
V_fixture_max= 0.568
|time   V(typ)   V(min)   V(max)
0s        450.6mV    436.2mV    471.2mV
407ps     450.7mV    436.4mV    473mV
511ps     459.7mV    436.2mV    549mV
567ps     494.6mV    438.3mV    581mV
617ps     529.3mV    451.7mV    599.7mV
663ps     556.1mV    478.3mV    611.2mV
762ps     592.2mV    534.4mV    624.4mV
902ps     612.7mV    579.5mV    631.1mV
1.1ns     620.2mV    599.6mV    633.6mV
10ns      622.6mV    605.9mV    634.5mV
[Falling Waveform]
R_fixture= 50.000
V_fixture= 0.550
V_fixture_min= 0.534
V_fixture_max= 0.568
|time   V(typ)   V(min)   V(max)
0s        622.6mV    605.9mV    634.5mV
390ps     622.7mV    605.9mV    635mV
497ps     619.1mV    606.7mV    537.6mV
575ps     542.5mV    605.6mV    502.2mV
608ps     517.5mV    593.6mV    493.9mV
655ps     493.6mV    552.5mV    485.9mV
762ps     467.2mV    482.6mV    476.9mV
863ps     457.8mV    456.5mV    473.8mV
1.002ns   453.3mV    443.4mV    472.4mV
10ns      450.6mV    436.2mV    471.2mV
[Falling Waveform]
R_fixture= 50.000
V_fixture= 0.0
V_fixture_min= 0.0
V_fixture_max= 0.0
|time   V(typ)   V(min)   V(max)
0s        127.6mV    131.3mV    111.2mV
389ps     128mV      131.3mV    112.4mV
489ps     126.9mV    132.6mV    48.44mV
565ps     70.71mV    132.4mV    22.86mV
642ps     32.7mV     89.56mV    11.21mV
693ps     20.37mV    54.55mV    7.165mV
762ps     11.14mV    28.61mV    3.994mV
879ps     4.333mV    10.66mV    1.646mV
1.08ns    1.117mV    2.531mV    559.2uV
10ns      2.28uV     12.08uV    1.045uV
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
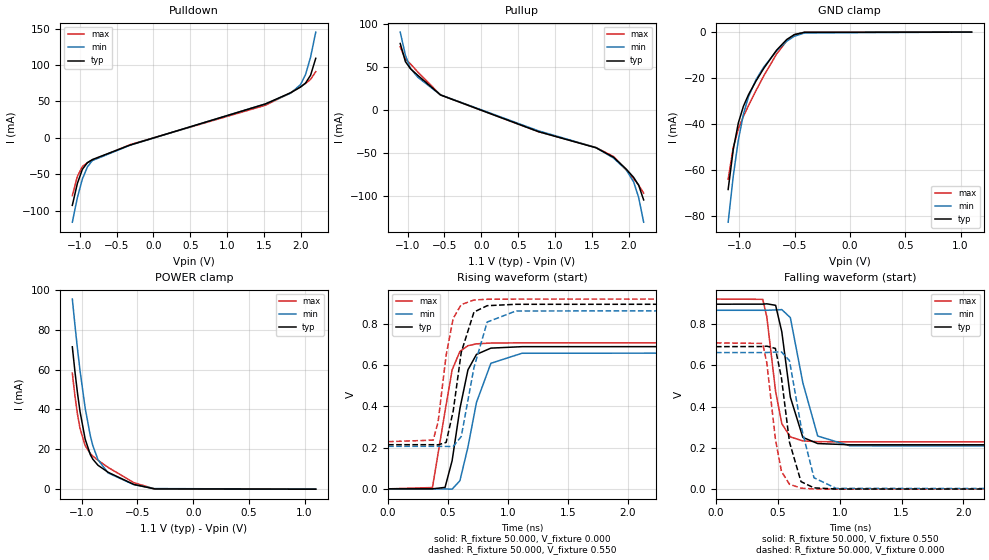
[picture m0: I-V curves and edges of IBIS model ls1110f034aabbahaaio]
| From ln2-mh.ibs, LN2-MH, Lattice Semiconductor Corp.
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|   Model ls1110f034aabbahaaio
[Model] ls1110f034aabbahaaio
| Clamp models do not include dynamic input termination. Please refer to
| the ls1110axxxaabbahaain model for input termination.
Model_type I/O
Polarity   Non-Inverting
Enable   Active-Low
Vinl =  0.200V
Vinh =  0.300V
Vmeas =  0.550V
Cref =  20.000pF
Rref =  50.000
Vref =  0.600V
C_comp   2.000pF   1.500pF   2.500pF
[Temperature Range]   25.000   0.125k   -40.000
[Voltage Range]   1.100V   1.070V   1.130V
[C Comp Corner]
C_comp   2.000pF   1.500pF   2.500pF
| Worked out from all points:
|   slope of the pulldown table from 0 to 0.165 V, typ, clamps not added: 31.9 ohm
|   slope of the pullup table from 0 to 0.165 V, typ, clamps not added: 29.4 ohm
|   GND clamp passes 1 mA (typ) near -0.50 V on its own axis
|   POWER clamp passes 1 mA (typ) near -0.45 V on its own axis
|   rising waveform, R_fixture 50.000, V_fixture 0.000: 20-80 % time 119ps typ, 144ps min, 106ps max; typ from 0 V to 0.691 V
|   rising waveform, R_fixture 50.000, V_fixture 0.550: 20-80 % time 106ps typ, 126ps min, 96.5ps max; typ from 0.214 V to 0.897 V
|   falling waveform, R_fixture 50.000, V_fixture 0.550: 20-80 % time 97.5ps typ, 120ps min, 88.5ps max; typ from 0.897 V to 0.214 V
|   falling waveform, R_fixture 50.000, V_fixture 0.000: 20-80 % time 94.6ps typ, 113ps min, 86.1ps max; typ from 0.691 V to 0 V
[Pulldown]
|Voltage   I(typ)   I(min)   I(max)
-1.1V     -92.77mA   -115.9mA   -79.48mA
-1.032V   -62.9mA    -82.39mA   -53.16mA
-964mV    -43.38mA   -56.66mA   -39.57mA
-896mV    -34.2mA    -40.07mA   -34.34mA
-828mV    -29.9mA    -31.24mA   -30.92mA
-318mV    -10.03mA   -10.28mA   -9.481mA
1.518V    46.44mA    46.55mA    44.66mA
1.858V    61.77mA    61.08mA    61.62mA
1.994V    69.6mA     72.99mA    70.2mA
2.062V    75.1mA     86.91mA    74.73mA
2.13V     85.87mA    110.7mA    80.09mA
2.2V      109.1mA    145.1mA    90.74mA
[Pullup]
|Voltage   I(typ)   I(min)   I(max)
-1.1V     77.78mA    91.11mA    73.88mA
-1.03V    56.62mA    64.12mA    59.36mA
-962mV    48.4mA     48.7mA     54.04mA
-860mV    40.43mA    38.2mA     44.29mA
-554mV    17.69mA    17.82mA    17.64mA
772mV     -25.08mA   -24.14mA   -25.2mA
1.554V    -44mA      -43.77mA   -43.68mA
1.792V    -55.1mA    -56.04mA   -54.26mA
1.962V    -68.78mA   -69.58mA   -69.63mA
2.064V    -78.52mA   -83.78mA   -80.12mA
2.132V    -87.69mA   -102.1mA   -87.58mA
2.2V      -104.9mA   -130.9mA   -97.03mA
[GND_clamp]
|Voltage   I(typ)   I(min)   I(max)
-1.1V     -68.65mA   -82.91mA   -64.16mA
-1.054V   -51.26mA   -62.87mA   -50.37mA
-1.008V   -39.63mA   -47.13mA   -42.26mA
-962mV    -32.34mA   -35.82mA   -36.73mA
-916mV    -27.28mA   -28.13mA   -32.02mA
-847mV    -21.22mA   -20.63mA   -25.4mA
-778mV    -15.81mA   -15.27mA   -19.09mA
-663mV    -7.926mA   -8.201mA   -9.607mA
-571mV    -3.246mA   -3.982mA   -3.828mA
-502mV    -1.097mA   -1.819mA   -1.164mA
-410mV    -96.97uA   -374.9uA   -57.53uA
1.1V      0A         0A         0A
[POWER_clamp]
|Voltage   I(typ)   I(min)   I(max)
-1.085V   71.41mA    95.35mA    58.18mA
-1.062V   59.23mA    82.55mA    46.99mA
-1.039V   48.36mA    70.56mA    37.71mA
-1.016V   38.97mA    59.53mA    30.53mA
-970mV    25.17mA    40.76mA    21.88mA
-924mV    17.37mA    26.93mA    17.87mA
-901mV    15.03mA    21.86mA    16.59mA
-855mV    12.01mA    14.79mA    14.5mA
-763mV    8.448mA    8.108mA    10.89mA
-533mV    2.369mA    2.267mA    3.272mA
-349mV    143.9uA    291.4uA    171.3uA
1.1V      0A         0A         0A
[Ramp]
| variable   typ   min   max
dV/dt_r   0.399/0.119n   0.382/0.144n   0.410/0.106n
dV/dt_f   0.402/0.104n   0.393/0.132n   0.404/91.485p
R_load = 50.000
[Rising Waveform]
R_fixture = 50.000
V_fixture = 0.000
V_fixture_min = 0.000
V_fixture_max = 0.000
|  time   V(typ)   V(min)   V(max)
0s        1.49uV     6.926uV    592.9nV
370ps     59.9uV     44.7uV     6.39mV
475ps     7.169mV    -385.2uV   376.7mV
534ps     136.9mV    -1.509mV   577.6mV
599ps     390.2mV    39.77mV    667.3mV
666ps     578mV      203.5mV    695mV
737ps     652.9mV    419.8mV    704mV
857ps     683.2mV    609.6mV    707.9mV
1.116ns   690.3mV    658.3mV    708.8mV
10ns      690.7mV    662mV      708.9mV
[Rising Waveform]
R_fixture = 50.000
V_fixture = 0.550
V_fixture_min = 0.534
V_fixture_max = 0.568
|  time   V(typ)   V(min)   V(max)
0s        214.4mV    206.4mV    229.1mV
376ps     214.4mV    206.4mV    236.5mV
417ps     213.9mV    206.4mV    324.8mV
484ps     225.4mV    205.9mV    648.5mV
543ps     377.9mV    205.8mV    827.8mV
610ps     663mV      254.1mV    894.7mV
716ps     858.4mV    588.3mV    916.8mV
826ps     889.2mV    809.6mV    920.4mV
1.066ns   896mV      863.6mV    921.3mV
10ns      896.5mV    867mV      921.4mV
[Falling Waveform]
R_fixture = 50.000
V_fixture = 0.550
V_fixture_min = 0.534
V_fixture_max = 0.568
|  time   V(typ)   V(min)   V(max)
0s        896.5mV    867mV      921.4mV
378ps     896.8mV    867mV      920.1mV
411ps     898.3mV    867.1mV    834.1mV
482ps     891.1mV    868.7mV    472.9mV
532ps     762.4mV    870.3mV    317.3mV
601ps     445.8mV    831.5mV    253.1mV
702ps     251mV      515.6mV    234mV
822ps     221.1mV    257.5mV    230.3mV
1.082ns   215.1mV    210.1mV    229.2mV
10ns      214.4mV    206.4mV    229.1mV
[Falling Waveform]
R_fixture = 50.000
V_fixture = 0.000
V_fixture_min = 0.000
V_fixture_max = 0.000
|  time   V(typ)   V(min)   V(max)
0s        690.7mV    662mV      708.9mV
377ps     691.3mV    662.1mV    706.4mV
411ps     693.1mV    662.4mV    611.2mV
480ps     682.2mV    664.4mV    243.5mV
529ps     540.2mV    665mV      86.3mV
594ps     228.1mV    623mV      23.71mV
687ps     36.5mV     306.7mV    4.786mV
792ps     6.295mV    55.25mV    1.122mV
971ps     782.9uV    3.882mV    206.2uV
10ns      1.49uV     6.926uV    592.9nV
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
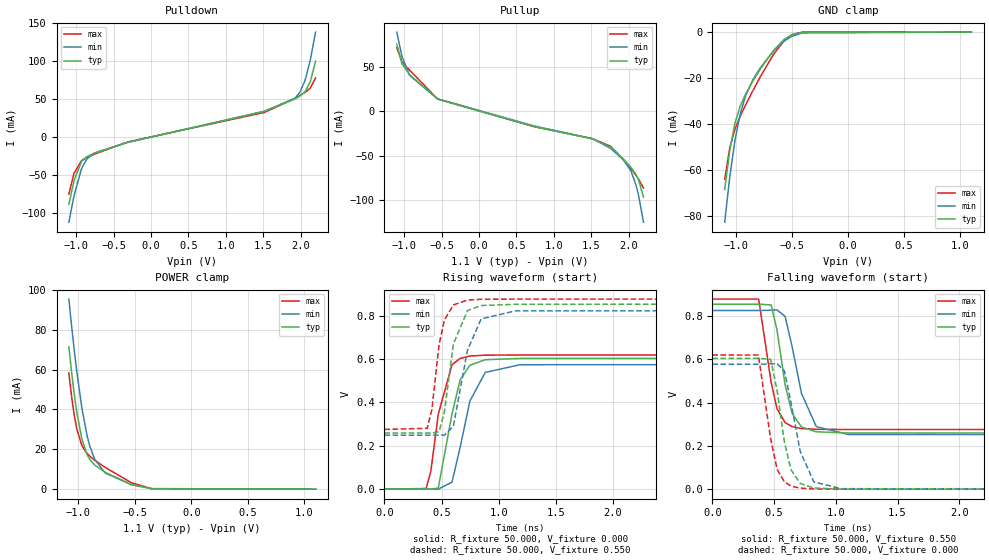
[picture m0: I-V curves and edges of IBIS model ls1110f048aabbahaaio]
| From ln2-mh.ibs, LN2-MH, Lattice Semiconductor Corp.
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|   Model ls1110f048aabbahaaio
[Model] ls1110f048aabbahaaio
| Clamp models do not include dynamic input termination. Please refer to
| the ls1110axxxaabbahaain model for input termination.
Model_type I/O
Polarity   Non-Inverting
Enable   Active-Low
Vinl =  0.200V
Vinh =  0.300V
Vmeas =  0.550V
Cref =  20.000pF
Rref =  50.000
Vref =  0.600V
C_comp   2.000pF   1.500pF   2.500pF
[Temperature Range]   25.000   0.125k   -40.000
[Voltage Range]   1.100V   1.070V   1.130V
[C Comp Corner]
C_comp   2.000pF   1.500pF   2.500pF
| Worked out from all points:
|   slope of the pulldown table from 0 to 0.165 V, typ, clamps not added: 44.4 ohm
|   slope of the pullup table from 0 to 0.165 V, typ, clamps not added: 40.6 ohm
|   GND clamp passes 1 mA (typ) near -0.50 V on its own axis
|   POWER clamp passes 1 mA (typ) near -0.45 V on its own axis
|   rising waveform, R_fixture 50.000, V_fixture 0.000: 20-80 % time 121ps typ, 149ps min, 106ps max; typ from 0 V to 0.604 V
|   rising waveform, R_fixture 50.000, V_fixture 0.550: 20-80 % time 101ps typ, 125ps min, 89.6ps max; typ from 0.259 V to 0.854 V
|   falling waveform, R_fixture 50.000, V_fixture 0.550: 20-80 % time 106ps typ, 133ps min, 95ps max; typ from 0.854 V to 0.259 V
|   falling waveform, R_fixture 50.000, V_fixture 0.000: 20-80 % time 102ps typ, 123ps min, 93.9ps max; typ from 0.604 V to 0 V
[Pulldown]
|Voltage   I(typ)   I(min)   I(max)
-1.1V     -88.71mA   -112.2mA   -75.25mA
-1.032V   -57.76mA   -77.86mA   -48.02mA
-930mV    -32.17mA   -41.77mA   -31.26mA
-862mV    -26.22mA   -29.4mA    -27.47mA
-760mV    -21.58mA   -21.29mA   -22.9mA
-318mV    -7.228mA   -7.436mA   -6.822mA
1.518V    33.49mA    33.69mA    32.15mA
1.926V    49.94mA    50.87mA    50.64mA
1.994V    53.77mA    59.12mA    54.52mA
2.062V    59.67mA    75.04mA    58.65mA
2.13V     72.64mA    101.3mA    64.17mA
2.2V      99.43mA    137.7mA    77.46mA
[Pullup]
|Voltage   I(typ)   I(min)   I(max)
-1.1V     75.12mA    88.71mA    71.1mA
-1.03V    52.9mA     61.03mA    55.16mA
-928mV    40.8mA     40.05mA    45.89mA
-554mV    13.4mA     13.73mA    13.48mA
738mV     -17.46mA   -16.8mA    -17.52mA
1.52V     -31.29mA   -31.13mA   -31.08mA
1.758V    -40.45mA   -41.8mA    -39.54mA
1.928V    -53.62mA   -54.61mA   -54.32mA
2.03V     -63.05mA   -66.96mA   -64.75mA
2.098V    -71.12mA   -82.44mA   -72.12mA
2.132V    -76.93mA   -93.92mA   -76.09mA
2.2V      -96.63mA   -124.9mA   -86.56mA
[GND_clamp]
|Voltage   I(typ)   I(min)   I(max)
-1.1V     -68.65mA   -82.91mA   -64.16mA
-1.054V   -51.26mA   -62.87mA   -50.37mA
-1.008V   -39.63mA   -47.13mA   -42.26mA
-962mV    -32.34mA   -35.82mA   -36.73mA
-916mV    -27.28mA   -28.13mA   -32.02mA
-847mV    -21.22mA   -20.63mA   -25.4mA
-778mV    -15.81mA   -15.27mA   -19.09mA
-663mV    -7.926mA   -8.201mA   -9.607mA
-571mV    -3.246mA   -3.982mA   -3.828mA
-502mV    -1.097mA   -1.819mA   -1.164mA
-410mV    -96.97uA   -374.9uA   -57.53uA
1.1V      0A         0A         0A
[POWER_clamp]
|Voltage   I(typ)   I(min)   I(max)
-1.085V   71.41mA    95.35mA    58.18mA
-1.062V   59.23mA    82.55mA    46.99mA
-1.039V   48.36mA    70.56mA    37.71mA
-1.016V   38.97mA    59.53mA    30.53mA
-970mV    25.17mA    40.76mA    21.88mA
-924mV    17.37mA    26.93mA    17.87mA
-901mV    15.03mA    21.86mA    16.59mA
-855mV    12.01mA    14.79mA    14.5mA
-763mV    8.448mA    8.108mA    10.89mA
-533mV    2.369mA    2.267mA    3.272mA
-349mV    143.9uA    291.4uA    171.3uA
1.1V      0A         0A         0A
[Ramp]
| variable   typ   min   max
dV/dt_r   0.345/0.122n   0.346/0.150n   0.372/0.107n
dV/dt_f   0.349/0.113n   0.341/0.149n   0.349/96.042p
R_load = 50.000
[Rising Waveform]
R_fixture = 50.000
V_fixture = 0.000
V_fixture_min = 0.000
V_fixture_max = 0.000
|  time   V(typ)   V(min)   V(max)
0s        2.075uV    7.548uV    855.7nV
365ps     80.04uV    55.65uV    2.522mV
406ps     -394.8uV   76.58uV    83.43mV
471ps     4.676mV    -290.7uV   346.1mV
591ps     347.5mV    32.2mV     574.5mV
662ps     504.1mV    192.1mV    603.5mV
747ps     571.8mV    405.9mV    614.5mV
882ps     597.6mV    538.9mV    618.6mV
1.187ns   603.4mV    574.5mV    619.5mV
10ns      603.7mV    576.8mV    619.5mV
[Rising Waveform]
R_fixture = 50.000
V_fixture = 0.550
V_fixture_min = 0.534
V_fixture_max = 0.568
|  time   V(typ)   V(min)   V(max)
0s        258.9mV    249.5mV    275.5mV
374ps     259mV      249.5mV    280.7mV
415ps     258.5mV    249.5mV    367.9mV
478ps     265.3mV    249.1mV    667.9mV
525ps     357.8mV    249.3mV    781.9mV
603ps     670mV      290mV      850.5mV
726ps     824.4mV    641.2mV    873.2mV
846ps     847.9mV    786mV      876.7mV
1.145ns   853.5mV    823.2mV    877.6mV
10ns      853.8mV    825mV      877.7mV
[Falling Waveform]
R_fixture = 50.000
V_fixture = 0.550
V_fixture_min = 0.534
V_fixture_max = 0.568
|  time   V(typ)   V(min)   V(max)
0s        853.8mV    825mV      877.7mV
375ps     854mV      825.1mV    877.9mV
476ps     851mV      826.4mV    493.6mV
523ps     737mV      828.1mV    372.1mV
589ps     482.4mV    798.1mV    307.6mV
646ps     349.9mV    658.1mV    288.7mV
722ps     287.4mV    442mV      279.9mV
842ps     264.8mV    288.9mV    276.5mV
1.099ns   259.4mV    252.7mV    275.6mV
10ns      258.9mV    249.5mV    275.5mV
[Falling Waveform]
R_fixture = 50.000
V_fixture = 0.000
V_fixture_min = 0.000
V_fixture_max = 0.000
|  time   V(typ)   V(min)   V(max)
0s        603.7mV    576.8mV    619.5mV
373ps     604.2mV    576.8mV    619.3mV
472ps     599.8mV    578.8mV    232.7mV
524ps     456.3mV    579.7mV    92.28mV
584ps     216.1mV    545.1mV    33.21mV
638ps     88.36mV    396mV      14.05mV
712ps     26.36mV    174mV      4.657mV
822ps     5.441mV    33.56mV    1.086mV
1.042ns   482uV      2.273mV    131.8uV
10ns      2.075uV    7.548uV    855.7nV
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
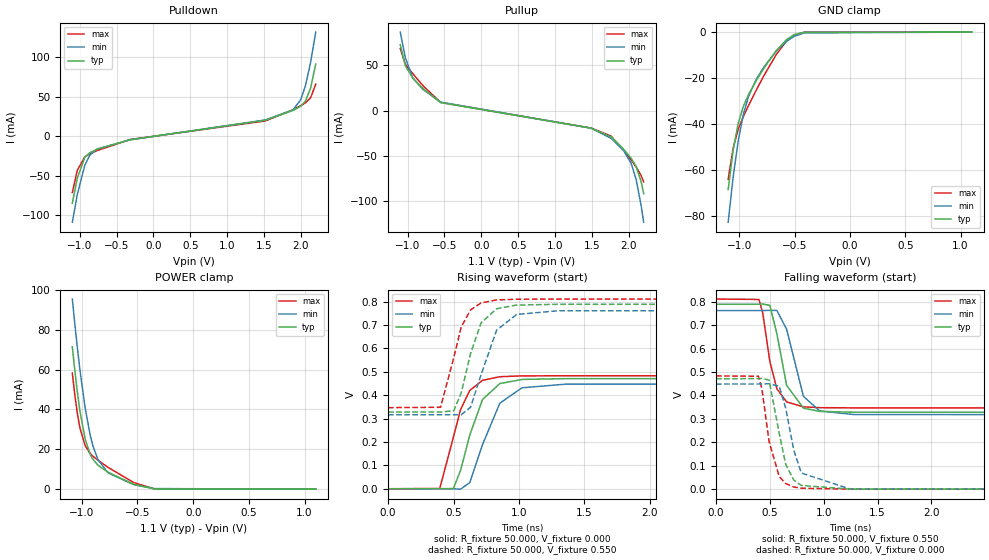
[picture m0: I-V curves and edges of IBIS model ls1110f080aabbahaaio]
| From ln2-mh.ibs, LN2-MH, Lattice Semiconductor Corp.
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|   Model ls1110f080aabbahaaio
[Model] ls1110f080aabbahaaio
| Clamp models do not include dynamic input termination. Please refer to
| the ls1110axxxaabbahaain model for input termination.
Model_type I/O
Polarity   Non-Inverting
Enable   Active-Low
Vinl =  0.200V
Vinh =  0.300V
Vmeas =  0.550V
Cref =  20.000pF
Rref =  50.000
Vref =  0.600V
C_comp   2.000pF   1.500pF   2.500pF
[Temperature Range]   25.000   0.125k   -40.000
[Voltage Range]   1.100V   1.070V   1.130V
[C Comp Corner]
C_comp   2.000pF   1.500pF   2.500pF
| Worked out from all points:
|   slope of the pulldown table from 0 to 0.165 V, typ, clamps not added: 73.8 ohm
|   slope of the pullup table from 0 to 0.165 V, typ, clamps not added: 65.1 ohm
|   GND clamp passes 1 mA (typ) near -0.50 V on its own axis
|   POWER clamp passes 1 mA (typ) near -0.45 V on its own axis
|   rising waveform, R_fixture 50.000, V_fixture 0.000: 20-80 % time 155ps typ, 179ps min, 139ps max; typ from 0 V to 0.471 V
|   rising waveform, R_fixture 50.000, V_fixture 0.550: 20-80 % time 135ps typ, 155ps min, 121ps max; typ from 0.328 V to 0.789 V
|   falling waveform, R_fixture 50.000, V_fixture 0.550: 20-80 % time 120ps typ, 141ps min, 110ps max; typ from 0.789 V to 0.328 V
|   falling waveform, R_fixture 50.000, V_fixture 0.000: 20-80 % time 115ps typ, 130ps min, 105ps max; typ from 0.471 V to 0 V
[Pulldown]
|Voltage   I(typ)   I(min)   I(max)
-1.1V     -85.01mA   -108.9mA   -71.31mA
-1.032V   -52.83mA   -73.64mA   -42.99mA
-930mV    -26.59mA   -36.48mA   -26.08mA
-862mV    -20.71mA   -23.94mA   -22.41mA
-760mV    -16.3mA    -15.99mA   -18.05mA
-318mV    -4.381mA   -4.551mA   -4.125mA
1.518V    20.39mA    20.71mA    19.49mA
1.892V    32.77mA    33.6mA     33.64mA
1.994V    37.99mA    46.04mA    38.71mA
2.062V    44.81mA    64.59mA    42.51mA
2.13V     60.93mA    93.6mA     48.72mA
2.2V      91.63mA    132.1mA    65.98mA
[Pullup]
|Voltage   I(typ)   I(min)   I(max)
-1.1V     72.9mA     86.81mA    68.71mA
-1.03V    49.54mA    58.38mA    51.21mA
-928mV    35.84mA    36.02mA    40.78mA
-792mV    24.52mA    23.51mA    27.68mA
-554mV    9.096mA    9.605mA    9.295mA
1.486V    -19.17mA   -19.12mA   -19.04mA
1.758V    -28.66mA   -30.43mA   -27.84mA
1.928V    -42.4mA    -43.91mA   -43.36mA
2.03V     -52.37mA   -57.85mA   -54.25mA
2.098V    -61.45mA   -75.77mA   -62.01mA
2.166V    -78.13mA   -104.6mA   -71.44mA
2.2V      -91.52mA   -122.9mA   -78.53mA
[GND_clamp]
|Voltage   I(typ)   I(min)   I(max)
-1.1V     -68.65mA   -82.91mA   -64.16mA
-1.054V   -51.26mA   -62.87mA   -50.37mA
-1.008V   -39.63mA   -47.13mA   -42.26mA
-962mV    -32.34mA   -35.82mA   -36.73mA
-916mV    -27.28mA   -28.13mA   -32.02mA
-847mV    -21.22mA   -20.63mA   -25.4mA
-778mV    -15.81mA   -15.27mA   -19.09mA
-663mV    -7.926mA   -8.201mA   -9.607mA
-571mV    -3.246mA   -3.982mA   -3.828mA
-502mV    -1.097mA   -1.819mA   -1.164mA
-410mV    -96.97uA   -374.9uA   -57.53uA
1.1V      0A         0A         0A
[POWER_clamp]
|Voltage   I(typ)   I(min)   I(max)
-1.085V   71.41mA    95.35mA    58.18mA
-1.062V   59.23mA    82.55mA    46.99mA
-1.039V   48.36mA    70.56mA    37.71mA
-1.016V   38.97mA    59.53mA    30.53mA
-970mV    25.17mA    40.76mA    21.88mA
-924mV    17.37mA    26.93mA    17.87mA
-901mV    15.03mA    21.86mA    16.59mA
-855mV    12.01mA    14.79mA    14.5mA
-763mV    8.448mA    8.108mA    10.89mA
-533mV    2.369mA    2.267mA    3.272mA
-349mV    143.9uA    291.4uA    171.3uA
1.1V      0A         0A         0A
[Ramp]
| variable   typ   min   max
dV/dt_r   0.283/0.155n   0.269/0.179n   0.290/0.139n
dV/dt_f   0.266/0.133n   0.261/0.162n   0.264/0.119n
R_load = 50.000
[Rising Waveform]
R_fixture = 50.000
V_fixture = 0.000
V_fixture_min = 0.000
V_fixture_max = 0.000
|  time   V(typ)   V(min)   V(max)
0s        1.577uV    10.97uV    1.615uV
395ps     184.2uV    131.5uV    1.164mV
499ps     902.7uV    -259.6uV   220.4mV
554ps     78.37mV    -1.745mV   338.5mV
624ps     229.2mV    26.08mV    420.3mV
722ps     382.2mV    189.1mV    463.9mV
854ps     449.8mV    365.9mV    479.2mV
1.023ns   467.6mV    431.8mV    482.7mV
1.363ns   471mV      447.7mV    483.3mV
10ns      471.2mV    448.6mV    483.4mV
[Rising Waveform]
R_fixture = 50.000
V_fixture = 0.550
V_fixture_min = 0.534
V_fixture_max = 0.568
|  time   V(typ)   V(min)   V(max)
0s        327.9mV    316.5mV    346.8mV
401ps     328mV      316.6mV    348.5mV
502ps     334mV      316.4mV    560.8mV
559ps     410mV      316.8mV    692.1mV
630ps     577.8mV    348.3mV    764.7mV
710ps     708.9mV    486.4mV    794.8mV
829ps     769.8mV    678.1mV    807.6mV
983ps     785.7mV    745.7mV    810.7mV
1.303ns   788.9mV    761.3mV    811.3mV
10ns      789.1mV    762.2mV    811.3mV
[Falling Waveform]
R_fixture = 50.000
V_fixture = 0.550
V_fixture_min = 0.534
V_fixture_max = 0.568
|  time   V(typ)   V(min)   V(max)
0s        789.1mV    762.2mV    811.3mV
399ps     789.3mV    762.2mV    809.7mV
434ps     790.2mV    762.2mV    752.4mV
500ps     784.5mV    763.2mV    544.9mV
565ps     664.1mV    762.9mV    428.6mV
656ps     442.9mV    682.4mV    372.4mV
812ps     345.8mV    395.9mV    351.1mV
963ps     332mV      333.6mV    347.9mV
1.282ns   328.4mV    318.4mV    346.9mV
10ns      327.9mV    316.5mV    346.8mV
[Falling Waveform]
R_fixture = 50.000
V_fixture = 0.000
V_fixture_min = 0.000
V_fixture_max = 0.000
|  time   V(typ)   V(min)   V(max)
0s        471.2mV    448.6mV    483.4mV
394ps     471.8mV    448.7mV    481.9mV
426ps     472.6mV    448.9mV    429.5mV
493ps     465.4mV    450.2mV    203.6mV
587ps     238.7mV    439.3mV    53.92mV
647ps     106.7mV    346.1mV    24.19mV
722ps     38.75mV    167.3mV    9.314mV
792ps     15.91mV    69.1mV     4.044mV
1.243ns   278.4uV    801.6uV    112.5uV
10ns      1.577uV    10.97uV    1.615uV
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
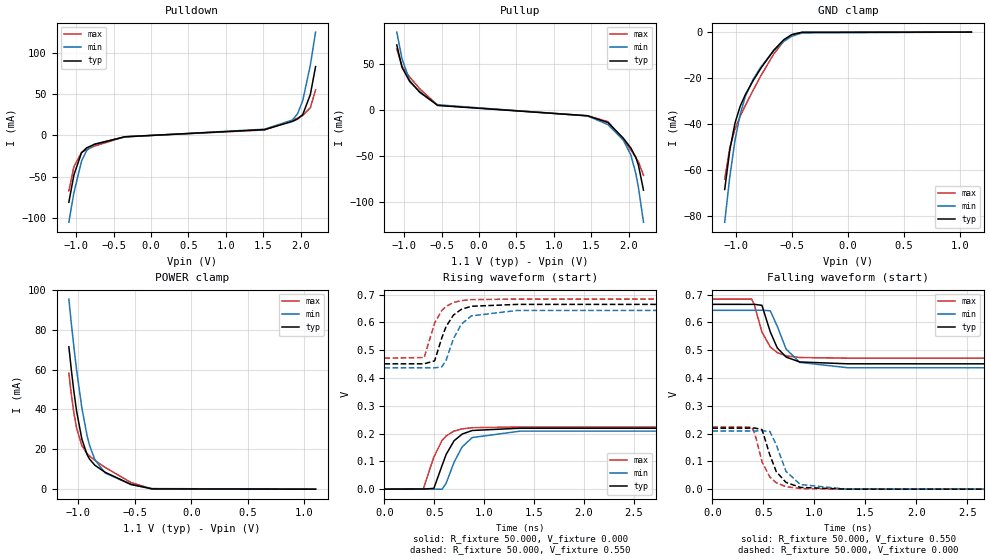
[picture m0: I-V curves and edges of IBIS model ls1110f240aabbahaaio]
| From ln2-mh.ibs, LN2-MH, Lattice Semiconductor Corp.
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|   Model ls1110f240aabbahaaio
[Model] ls1110f240aabbahaaio
| Clamp models do not include dynamic input termination. Please refer to
| the ls1110axxxaabbahaain model for input termination.
Model_type I/O
Polarity   Non-Inverting
Enable   Active-Low
Vinl =  0.200V
Vinh =  0.300V
Vmeas =  0.550V
Cref =  20.000pF
Rref =  50.000
Vref =  0.600V
C_comp   2.000pF   1.500pF   2.500pF
[Temperature Range]   25.000   0.125k   -40.000
[Voltage Range]   1.100V   1.070V   1.130V
[C Comp Corner]
C_comp   2.000pF   1.500pF   2.500pF
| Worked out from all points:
|   slope of the pulldown table from 0 to 0.165 V, typ, clamps not added: 226 ohm
|   slope of the pullup table from 0 to 0.165 V, typ, clamps not added: 189 ohm
|   GND clamp passes 1 mA (typ) near -0.50 V on its own axis
|   POWER clamp passes 1 mA (typ) near -0.45 V on its own axis
|   rising waveform, R_fixture 50.000, V_fixture 0.000: 20-80 % time 160ps typ, 174ps min, 149ps max; typ from 0 V to 0.219 V
|   rising waveform, R_fixture 50.000, V_fixture 0.550: 20-80 % time 145ps typ, 159ps min, 135ps max; typ from 0.451 V to 0.665 V
|   falling waveform, R_fixture 50.000, V_fixture 0.550: 20-80 % time 141ps typ, 153ps min, 134ps max; typ from 0.665 V to 0.451 V
|   falling waveform, R_fixture 50.000, V_fixture 0.000: 20-80 % time 136ps typ, 146ps min, 130ps max; typ from 0.219 V to 0 V
[Pulldown]
|Voltage   I(typ)   I(min)   I(max)
-1.1V     -81.17mA   -105.4mA   -67.34mA
-1.032V   -47.86mA   -69.27mA   -37.92mA
-930mV    -20.93mA   -31.09mA   -20.82mA
-862mV    -15.12mA   -18.39mA   -17.27mA
-760mV    -10.94mA   -10.6mA    -13.12mA
-352mV    -1.715mA   -1.886mA   -1.639mA
1.518V    7.039mA    7.489mA    6.6mA
1.892V    16.99mA    18.71mA    18.2mA
1.96V     19.93mA    26.39mA    21.06mA
2.028V    25.15mA    42.13mA    24.19mA
2.13V     49.57mA    85.28mA    33.6mA
2.2V      83.5mA     125.4mA    55.21mA
[Pullup]
|Voltage   I(typ)   I(min)   I(max)
-1.1V     70.38mA    84.41mA    66.13mA
-1.03V    46.02mA    55.41mA    47.25mA
-928mV    30.83mA    31.86mA    35.64mA
-792mV    19.37mA    18.63mA    22.71mA
-554mV    4.731mA    5.427mA    5.061mA
1.452V    -6.529mA   -6.64mA    -6.444mA
1.724V    -13.8mA    -16.09mA   -12.89mA
1.928V    -30.66mA   -32.78mA   -31.94mA
2.03V     -41.41mA   -48.75mA   -43.49mA
2.098V    -51.87mA   -69.53mA   -51.8mA
2.132V    -60.12mA   -84.3mA    -56.57mA
2.2V      -87.31mA   -122.1mA   -71.2mA
[GND_clamp]
|Voltage   I(typ)   I(min)   I(max)
-1.1V     -68.65mA   -82.91mA   -64.16mA
-1.054V   -51.26mA   -62.87mA   -50.37mA
-1.008V   -39.63mA   -47.13mA   -42.26mA
-962mV    -32.34mA   -35.82mA   -36.73mA
-916mV    -27.28mA   -28.13mA   -32.02mA
-847mV    -21.22mA   -20.63mA   -25.4mA
-778mV    -15.81mA   -15.27mA   -19.09mA
-663mV    -7.926mA   -8.201mA   -9.607mA
-571mV    -3.246mA   -3.982mA   -3.828mA
-502mV    -1.097mA   -1.819mA   -1.164mA
-410mV    -96.97uA   -374.9uA   -57.53uA
1.1V      0A         0A         0A
[POWER_clamp]
|Voltage   I(typ)   I(min)   I(max)
-1.085V   71.41mA    95.35mA    58.18mA
-1.062V   59.23mA    82.55mA    46.99mA
-1.039V   48.36mA    70.56mA    37.71mA
-1.016V   38.97mA    59.53mA    30.53mA
-970mV    25.17mA    40.76mA    21.88mA
-924mV    17.37mA    26.93mA    17.87mA
-901mV    15.03mA    21.86mA    16.59mA
-855mV    12.01mA    14.79mA    14.5mA
-763mV    8.448mA    8.108mA    10.89mA
-533mV    2.369mA    2.267mA    3.272mA
-349mV    143.9uA    291.4uA    171.3uA
1.1V      0A         0A         0A
[Ramp]
| variable   typ   min   max
dV/dt_r   0.132/0.160n   0.125/0.174n   0.134/0.149n
dV/dt_f   0.119/0.150n   0.117/0.169n   0.115/0.140n
R_load = 50.000
[Rising Waveform]
R_fixture = 50.000
V_fixture = 0.000
V_fixture_min = 0.000
V_fixture_max = 0.000
|  time   V(typ)   V(min)   V(max)
0s        2.527uV    12.65uV    1.11uV
389ps     346.7uV    169.2uV    728.8uV
495ps     2.515mV    -39.9uV    115.4mV
578ps     85.34mV    -195.5uV   175.5mV
618ps     124.6mV    20.99mV    191.2mV
698ps     174mV      96.7mV     208.8mV
779ps     198mV      152mV      216.8mV
880ps     210.9mV    185.5mV    221mV
1.36ns    219.1mV    208.6mV    223.5mV
10ns      219.3mV    209.1mV    223.6mV
[Rising Waveform]
R_fixture = 50.000
V_fixture = 0.550
V_fixture_min = 0.534
V_fixture_max = 0.568
|  time   V(typ)   V(min)   V(max)
0s        450.6mV    436.2mV    471.2mV
398ps     450.8mV    436.4mV    473.3mV
503ps     461.4mV    436.2mV    597.2mV
574ps     543.1mV    439.7mV    642.3mV
617ps     584.4mV    462.6mV    657.1mV
691ps     625.9mV    540.7mV    671.2mV
769ps     646.5mV    592.6mV    678mV
871ps     657.8mV    623.3mV    681.6mV
1.331ns   664.5mV    642.8mV    683.7mV
10ns      664.7mV    643.2mV    683.7mV
[Falling Waveform]
R_fixture = 50.000
V_fixture = 0.550
V_fixture_min = 0.534
V_fixture_max = 0.568
|  time   V(typ)   V(min)   V(max)
0s        664.7mV    643.2mV    683.7mV
385ps     664.6mV    643.1mV    683.6mV
411ps     664.8mV    643.2mV    663.6mV
486ps     661.2mV    643.6mV    565.5mV
568ps     565.8mV    641.6mV    511.3mV
637ps     507.8mV    585.4mV    491.1mV
723ps     475.2mV    504.1mV    479.6mV
857ps     457.5mV    456mV      473.5mV
1.331ns   450.8mV    436.6mV    471.2mV
10ns      450.6mV    436.2mV    471.2mV
[Falling Waveform]
R_fixture = 50.000
V_fixture = 0.000
V_fixture_min = 0.000
V_fixture_max = 0.000
|  time   V(typ)   V(min)   V(max)
0s        219.3mV    209.1mV    223.6mV
386ps     219.4mV    209.1mV    223mV
417ps     219.9mV    209.1mV    199.5mV
488ps     213.8mV    210mV      97.41mV
564ps     122.8mV    207.5mV    43.7mV
627ps     63.04mV    159.7mV    22.96mV
722ps     24.34mV    64.36mV    8.925mV
863ps     6.321mV    16.69mV    2.313mV
1.313ns   169.4uV    422.4uV    71.99uV
10ns      2.527uV    12.65uV    1.11uV
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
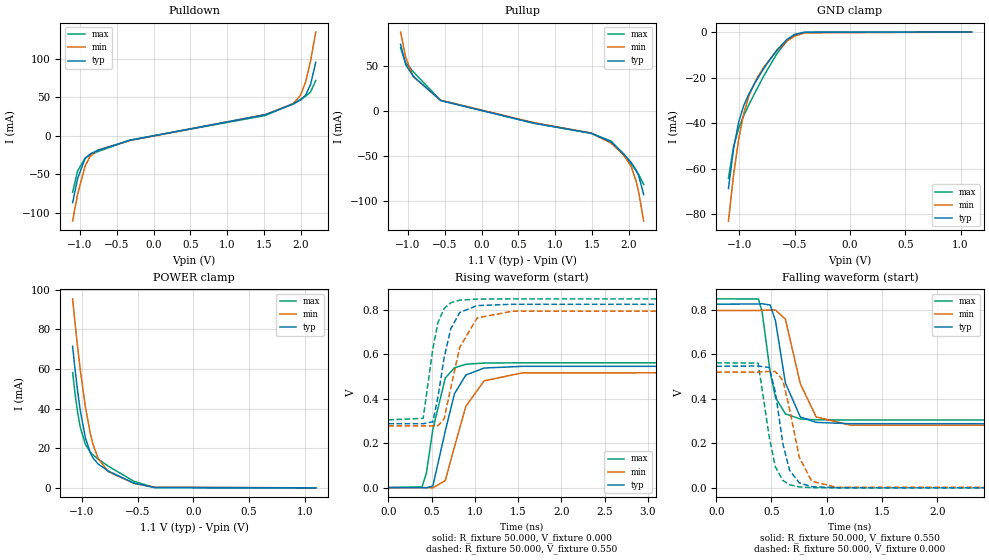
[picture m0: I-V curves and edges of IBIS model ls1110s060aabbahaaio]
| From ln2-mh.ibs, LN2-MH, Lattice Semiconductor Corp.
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|   Model ls1110s060aabbahaaio
[Model] ls1110s060aabbahaaio
| Clamp models do not include dynamic input termination. Please refer to
| the ls1110axxxaabbahaain model for input termination.
Model_type I/O
Polarity   Non-Inverting
Enable   Active-Low
Vinl =  0.200V
Vinh =  0.300V
Vmeas =  0.550V
Cref =  20.000pF
Rref =  50.000
Vref =  0.600V
C_comp   2.000pF   1.500pF   2.500pF
[Temperature Range]   25.000   0.125k   -40.000
[Voltage Range]   1.100V   1.070V   1.130V
[C Comp Corner]
C_comp   2.000pF   1.500pF   2.500pF
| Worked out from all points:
|   slope of the pulldown table from 0 to 0.165 V, typ, clamps not added: 54.8 ohm
|   slope of the pullup table from 0 to 0.165 V, typ, clamps not added: 49.8 ohm
|   GND clamp passes 1 mA (typ) near -0.50 V on its own axis
|   POWER clamp passes 1 mA (typ) near -0.45 V on its own axis
|   rising waveform, R_fixture 50.000, V_fixture 0.000: 20-80 % time 188ps typ, 240ps min, 153ps max; typ from 0 V to 0.547 V
|   rising waveform, R_fixture 50.000, V_fixture 0.550: 20-80 % time 156ps typ, 195ps min, 125ps max; typ from 0.288 V to 0.826 V
|   falling waveform, R_fixture 50.000, V_fixture 0.550: 20-80 % time 117ps typ, 151ps min, 102ps max; typ from 0.826 V to 0.288 V
|   falling waveform, R_fixture 50.000, V_fixture 0.000: 20-80 % time 110ps typ, 133ps min, 100ps max; typ from 0.547 V to 0 V
[Pulldown]
|Voltage   I(typ)   I(min)   I(max)
-1.1V     -86.81mA   -110.5mA   -73.32mA
-1.032V   -55.33mA   -75.72mA   -45.62mA
-930mV    -29.48mA   -39.18mA   -28.81mA
-862mV    -23.57mA   -26.75mA   -25.08mA
-760mV    -19.04mA   -18.74mA   -20.61mA
-318mV    -5.87mA    -6.055mA   -5.557mA
1.518V    27.25mA    27.47mA    26.2mA
1.892V    40.87mA    41.2mA     41.62mA
1.994V    46.21mA    52.59mA    47.06mA
2.062V    52.43mA    69.57mA    51.01mA
2.13V     66.65mA    96.98mA    56.74mA
2.2V      95.12mA    134.3mA    71.6mA
[Pullup]
|Voltage   I(typ)   I(min)   I(max)
-1.1V     73.86mA    87.51mA    69.82mA
-1.03V    51.14mA    59.54mA    53.19mA
-928mV    38.37mA    37.98mA    43.44mA
-554mV    11.32mA    11.71mA    11.49mA
704mV     -13.66mA   -13.1mA    -13.73mA
1.486V    -25.01mA   -24.74mA   -24.92mA
1.758V    -34.49mA   -35.98mA   -33.68mA
1.928V    -47.8mA    -48.97mA   -48.67mA
2.03V     -57.4mA    -61.9mA    -59.23mA
2.098V    -65.83mA   -78.31mA   -66.71mA
2.132V    -72.05mA   -90.37mA   -70.79mA
2.2V      -93.13mA   -122.5mA   -81.91mA
[GND_clamp]
|Voltage   I(typ)   I(min)   I(max)
-1.1V     -68.65mA   -82.91mA   -64.16mA
-1.054V   -51.26mA   -62.87mA   -50.37mA
-1.008V   -39.63mA   -47.13mA   -42.26mA
-962mV    -32.34mA   -35.82mA   -36.73mA
-916mV    -27.28mA   -28.13mA   -32.02mA
-847mV    -21.22mA   -20.63mA   -25.4mA
-778mV    -15.81mA   -15.27mA   -19.09mA
-663mV    -7.926mA   -8.201mA   -9.607mA
-571mV    -3.246mA   -3.982mA   -3.828mA
-502mV    -1.097mA   -1.819mA   -1.164mA
-410mV    -96.97uA   -374.9uA   -57.53uA
1.1V      0A         0A         0A
[POWER_clamp]
|Voltage   I(typ)   I(min)   I(max)
-1.085V   71.41mA    95.35mA    58.18mA
-1.062V   59.23mA    82.55mA    46.99mA
-1.039V   48.36mA    70.56mA    37.71mA
-1.016V   38.97mA    59.53mA    30.53mA
-970mV    25.17mA    40.76mA    21.88mA
-924mV    17.37mA    26.93mA    17.87mA
-901mV    15.03mA    21.86mA    16.59mA
-855mV    12.01mA    14.79mA    14.5mA
-763mV    8.448mA    8.108mA    10.89mA
-533mV    2.369mA    2.267mA    3.272mA
-349mV    143.9uA    291.4uA    171.3uA
1.1V      0A         0A         0A
[Ramp]
| variable   typ   min   max
dV/dt_r   0.328/0.189n   0.312/0.240n   0.337/0.154n
dV/dt_f   0.314/0.132n   0.307/0.182n   0.314/0.106n
R_load = 50.000
[Rising Waveform]
R_fixture = 50.000
V_fixture = 0.000
V_fixture_min = 0.000
V_fixture_max = 0.000
|  time   V(typ)   V(min)   V(max)
0s        1.692uV    8.245uV    473.4nV
389ps     -95.15uV   73.36uV    3.443mV
439ps     -1.056mV   62.18uV    64.28mV
515ps     7.945mV    -893.2uV   263.4mV
658ps     255.1mV    31.55mV    493.3mV
764ps     422.6mV    183.6mV    539.2mV
896ps     506.8mV    365.9mV    555.2mV
1.107ns   538.2mV    480.8mV    560.7mV
1.546ns   545.9mV    516.1mV    561.9mV
10ns      546.6mV    520.5mV    562mV
[Rising Waveform]
R_fixture = 50.000
V_fixture = 0.550
V_fixture_min = 0.534
V_fixture_max = 0.568
|  time   V(typ)   V(min)   V(max)
0s        287.8mV    277.6mV    304.9mV
402ps     287.5mV    277.7mV    311.7mV
515ps     296.5mV    277.3mV    627.2mV
575ps     411.5mV    278.9mV    744.8mV
645ps     585.3mV    309.9mV    806.4mV
722ps     715.6mV    451mV      832.3mV
826ps     788.6mV    632.1mV    843.9mV
1.026ns   819.3mV    763.8mV    848.6mV
1.432ns   825.3mV    794mV      849.5mV
10ns      825.8mV    797.4mV    849.6mV
[Falling Waveform]
R_fixture = 50.000
V_fixture = 0.550
V_fixture_min = 0.534
V_fixture_max = 0.568
|  time   V(typ)   V(min)   V(max)
0s        825.8mV    797.4mV    849.6mV
382ps     826.5mV    797.5mV    849.2mV
415ps     827.8mV    797.7mV    791.4mV
488ps     821.9mV    799.4mV    519.9mV
536ps     751.1mV    799.5mV    406.9mV
626ps     471.3mV    758.4mV    332.3mV
761ps     318.6mV    468mV      309.7mV
904ps     294.3mV    318.9mV    305.9mV
1.211ns   288.5mV    282.1mV    305mV
10ns      287.8mV    277.6mV    304.9mV
[Falling Waveform]
R_fixture = 50.000
V_fixture = 0.000
V_fixture_min = 0.000
V_fixture_max = 0.000
|  time   V(typ)   V(min)   V(max)
0s        546.6mV    520.5mV    562mV
379ps     547.8mV    520.6mV    560.8mV
481ps     540.5mV    523.6mV    224.6mV
535ps     430mV      522.9mV    94.17mV
604ps     195.2mV    482.7mV    32.74mV
664ps     78.61mV    352.4mV    13.77mV
751ps     22.48mV    138.3mV    4.274mV
864ps     5.306mV    29.7mV     1.104mV
1.092ns   583.8uV    2.502mV    142.2uV
10ns      1.692uV    8.245uV    473.4nV
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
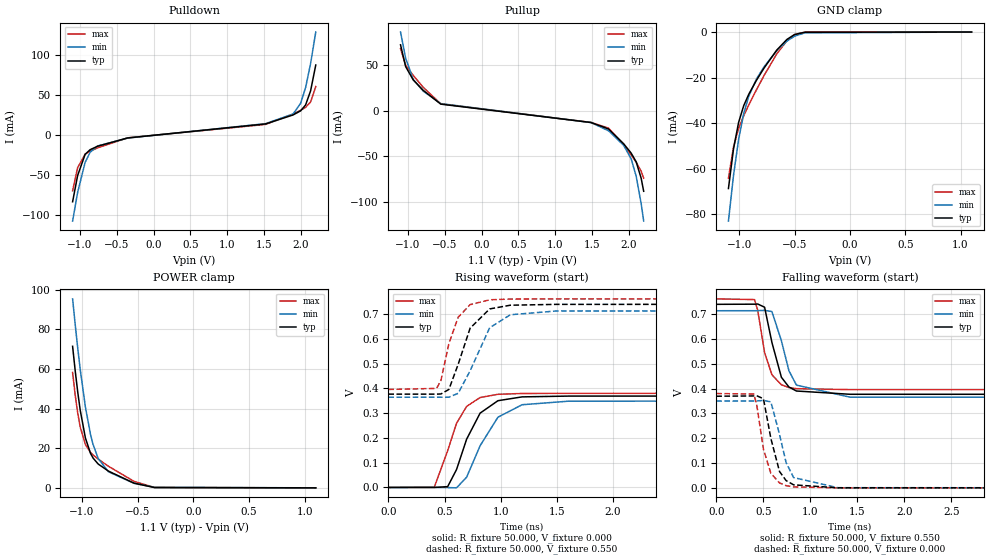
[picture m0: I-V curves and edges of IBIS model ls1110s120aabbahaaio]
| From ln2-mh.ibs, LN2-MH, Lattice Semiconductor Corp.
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|   Model ls1110s120aabbahaaio
[Model] ls1110s120aabbahaaio
| Clamp models do not include dynamic input termination. Please refer to
| the ls1110axxxaabbahaain model for input termination.
Model_type I/O
Polarity   Non-Inverting
Enable   Active-Low
Vinl =  0.200V
Vinh =  0.300V
Vmeas =  0.550V
Cref =  20.000pF
Rref =  50.000
Vref =  0.600V
C_comp   2.000pF   1.500pF   2.500pF
[Temperature Range]   25.000   0.125k   -40.000
[Voltage Range]   1.100V   1.070V   1.130V
[C Comp Corner]
C_comp   2.000pF   1.500pF   2.500pF
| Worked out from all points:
|   slope of the pulldown table from 0 to 0.165 V, typ, clamps not added: 108 ohm
|   slope of the pullup table from 0 to 0.165 V, typ, clamps not added: 95.2 ohm
|   GND clamp passes 1 mA (typ) near -0.50 V on its own axis
|   POWER clamp passes 1 mA (typ) near -0.45 V on its own axis
|   rising waveform, R_fixture 50.000, V_fixture 0.000: 20-80 % time 201ps typ, 240ps min, 173ps max; typ from 0 V to 0.369 V
|   rising waveform, R_fixture 50.000, V_fixture 0.550: 20-80 % time 163ps typ, 200ps min, 136ps max; typ from 0.377 V to 0.739 V
|   falling waveform, R_fixture 50.000, V_fixture 0.550: 20-80 % time 132ps typ, 154ps min, 122ps max; typ from 0.739 V to 0.377 V
|   falling waveform, R_fixture 50.000, V_fixture 0.000: 20-80 % time 123ps typ, 136ps min, 116ps max; typ from 0.369 V to 0 V
[Pulldown]
|Voltage   I(typ)   I(min)   I(max)
-1.1V     -83.17mA   -107.2mA   -69.44mA
-1.032V   -50.45mA   -71.54mA   -40.61mA
-930mV    -23.9mA    -33.9mA    -23.62mA
-862mV    -18.05mA   -21.29mA   -20mA
-760mV    -13.75mA   -13.42mA   -15.74mA
-352mV    -3.405mA   -3.591mA   -3.262mA
1.518V    14.06mA    14.41mA    13.46mA
1.892V    25.3mA     26.48mA    26.4mA
1.994V    30.4mA     39.74mA    31.14mA
2.062V    37.79mA    59.46mA    34.81mA
2.13V     55.42mA    89.57mA    41.52mA
2.2V      87.69mA    128.9mA    60.76mA
[Pullup]
|Voltage   I(typ)   I(min)   I(max)
-1.1V     71.68mA    85.61mA    67.47mA
-1.03V    47.83mA    56.93mA    49.31mA
-928mV    33.42mA    33.98mA    38.33mA
-792mV    22.03mA    21.13mA    25.32mA
-554mV    6.994mA    7.569mA    7.286mA
1.486V    -13.06mA   -13.14mA   -12.99mA
1.724V    -20.14mA   -22.1mA    -19.26mA
1.928V    -36.24mA   -37.97mA   -37.39mA
2.03V     -46.41mA   -52.61mA   -48.41mA
2.098V    -55.96mA   -71.57mA   -56.29mA
2.166V    -73.86mA   -101.6mA   -66.17mA
2.2V      -88.05mA   -120.5mA   -73.84mA
[GND_clamp]
|Voltage   I(typ)   I(min)   I(max)
-1.1V     -68.65mA   -82.91mA   -64.16mA
-1.054V   -51.26mA   -62.87mA   -50.37mA
-1.008V   -39.63mA   -47.13mA   -42.26mA
-962mV    -32.34mA   -35.82mA   -36.73mA
-916mV    -27.28mA   -28.13mA   -32.02mA
-847mV    -21.22mA   -20.63mA   -25.4mA
-778mV    -15.81mA   -15.27mA   -19.09mA
-663mV    -7.926mA   -8.201mA   -9.607mA
-571mV    -3.246mA   -3.982mA   -3.828mA
-502mV    -1.097mA   -1.819mA   -1.164mA
-410mV    -96.97uA   -374.9uA   -57.53uA
1.1V      0A         0A         0A
[POWER_clamp]
|Voltage   I(typ)   I(min)   I(max)
-1.085V   71.41mA    95.35mA    58.18mA
-1.062V   59.23mA    82.55mA    46.99mA
-1.039V   48.36mA    70.56mA    37.71mA
-1.016V   38.97mA    59.53mA    30.53mA
-970mV    25.17mA    40.76mA    21.88mA
-924mV    17.37mA    26.93mA    17.87mA
-901mV    15.03mA    21.86mA    16.59mA
-855mV    12.01mA    14.79mA    14.5mA
-763mV    8.448mA    8.108mA    10.89mA
-533mV    2.369mA    2.267mA    3.272mA
-349mV    143.9uA    291.4uA    171.3uA
1.1V      0A         0A         0A
[Ramp]
| variable   typ   min   max
dV/dt_r   0.221/0.201n   0.210/0.241n   0.228/0.173n
dV/dt_f   0.207/0.149n   0.203/0.182n   0.205/0.134n
R_load = 50.000
[Rising Waveform]
R_fixture = 50.000
V_fixture = 0.000
V_fixture_min = 0.000
V_fixture_max = 0.000
|  time   V(typ)   V(min)   V(max)
0s        2.818uV    12.02uV    614.4nV
409ps     68.25uV    189.8uV    1.421mV
528ps     3.278mV    -560uV     148.1mV
607ps     72.19mV    -1.55mV    258.9mV
697ps     194.9mV    41.66mV    327.3mV
817ps     300mV      168.4mV    363mV
976ps     350.2mV    283.7mV    376mV
1.191ns   365.6mV    333.9mV    379.3mV
1.606ns   368.8mV    348.3mV    379.9mV
10ns      369mV      349.6mV    379.9mV
[Rising Waveform]
R_fixture = 50.000
V_fixture = 0.550
V_fixture_min = 0.534
V_fixture_max = 0.568
|  time   V(typ)   V(min)   V(max)
0s        376.7mV    364.2mV    395.6mV
430ps     376.7mV    364.4mV    399.7mV
469ps     377.4mV    364.3mV    433.4mV
539ps     395.7mV    364.4mV    580.7mV
622ps     497.5mV    380.2mV    687.2mV
728ps     642.9mV    471mV      737.8mV
902ps     720.6mV    644.6mV    757.4mV
1.086ns   735.6mV    697mV      760.5mV
1.496ns   739mV      712.3mV    761.1mV
10ns      739.2mV    713.4mV    761.2mV
[Falling Waveform]
R_fixture = 50.000
V_fixture = 0.550
V_fixture_min = 0.534
V_fixture_max = 0.568
|  time   V(typ)   V(min)   V(max)
0s        739.2mV    713.4mV    761.2mV
407ps     739.8mV    713.5mV    758.3mV
441ps     740.5mV    713.7mV    714.9mV
514ps     727.6mV    714.8mV    544.7mV
592ps     585.7mV    710mV      455.5mV
693ps     445.2mV    592.3mV    415.1mV
773ps     406.2mV    471.7mV    404mV
853ps     390mV      413.8mV    399.5mV
1.423ns   376.9mV    365.3mV    395.7mV
10ns      376.7mV    364.2mV    395.6mV
[Falling Waveform]
R_fixture = 50.000
V_fixture = 0.000
V_fixture_min = 0.000
V_fixture_max = 0.000
|  time   V(typ)   V(min)   V(max)
0s        369mV      349.6mV    379.9mV
399ps     370.2mV    349.7mV    377.9mV
430ps     371.1mV    350.1mV    335.8mV
502ps     358.8mV    352.1mV    155.5mV
581ps     198.6mV    346.3mV    58.42mV
673ps     65.71mV    214.6mV    19.74mV
743ps     29.25mV    101.7mV    8.943mV
823ps     12.09mV    41.39mV    3.768mV
1.293ns   237.8uV    662.1uV    96.89uV
10ns      2.818uV    12.02uV    614.4nV
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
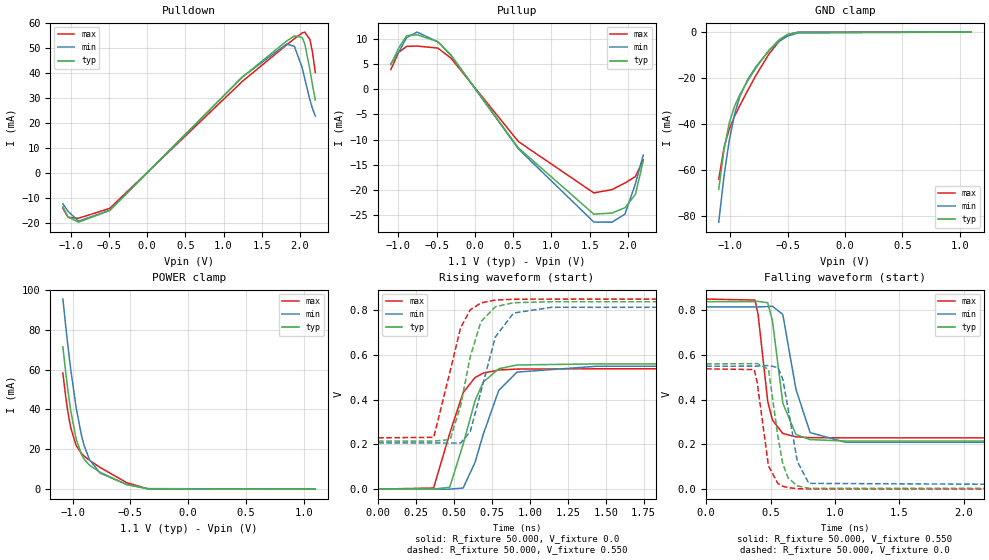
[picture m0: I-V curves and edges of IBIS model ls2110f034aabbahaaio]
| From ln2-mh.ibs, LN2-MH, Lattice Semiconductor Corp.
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|   Model ls2110f034aabbahaaio
[Model] ls2110f034aabbahaaio
| Clamp models do not include dynamic input termination. Please refer to
| the ls2110axxxaabbahaain model for input termination.
Model_type I/O
Polarity   Non-Inverting
Enable   Active-Low
Vinl =  0.200V
Vinh =  0.300V
Vmeas =  0.550V
Cref =  20.000pF
Rref =  50.000
Vref =  0.600V
C_comp   2.000pF   1.500pF   2.500pF
[Temperature Range]   25.000   0.125k   -40.000
[Voltage Range]   1.100V   1.070V   1.130V
[C Comp Corner]
C_comp   2.000pF   1.500pF   2.500pF
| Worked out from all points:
|   slope of the pulldown table from 0 to 0.165 V, typ, clamps not added: 31.9 ohm
|   slope of the pullup table from 0 to 0.165 V, typ, clamps not added: 45.3 ohm
|   GND clamp passes 1 mA (typ) near -0.50 V on its own axis
|   POWER clamp passes 1 mA (typ) near -0.45 V on its own axis
|   rising waveform, R_fixture 50.000, V_fixture 0.0: 20-80 % time 141ps typ, 160ps min, 140ps max; typ from 0 V to 0.56 V
|   rising waveform, R_fixture 50.000, V_fixture 0.550: 20-80 % time 122ps typ, 138ps min, 119ps max; typ from 0.214 V to 0.837 V
|   falling waveform, R_fixture 50.000, V_fixture 0.550: 20-80 % time 87.6ps typ, 111ps min, 77.9ps max; typ from 0.837 V to 0.214 V
|   falling waveform, R_fixture 50.000, V_fixture 0.0: 20-80 % time 83.3ps typ, 101ps min, 75.8ps max; typ from 0.56 V to 0 V
[Pulldown]
|Voltage   I(typ)   I(min)   I(max)
-1.1V     -13.39mA   -12.19mA   -13.95mA
-1.032V   -17.38mA   -15.19mA   -17.59mA
-896mV    -19.51mA   -19.08mA   -17.94mA
-488mV    -14.86mA   -14.78mA   -14.01mA
1.246V    38.35mA    38.42mA    36.65mA
1.824V    52.74mA    51.53mA    51.2mA
1.926V    54.81mA    50.69mA    53.7mA
2.028V    54.17mA    42.2mA     55.99mA
2.062V    51.67mA    37.77mA    56.33mA
2.13V     41.38mA    29.25mA    53.34mA
2.164V    35.13mA    25.8mA     48.11mA
2.2V      29.25mA    22.8mA     40.19mA
[Pullup]
|Voltage   I(typ)   I(min)   I(max)
-1.1V     4.877mA    5.08mA     3.939mA
-996mV    8.246mA    7.456mA    7.374mA
-894mV    10.69mA    10.28mA    8.55mA
-758mV    10.87mA    11.4mA     8.618mA
-486mV    9.499mA    9.475mA    8.22mA
-316mV    6.88mA     6.811mA    6.248mA
568mV     -11.67mA   -11.87mA   -10.41mA
1.554V    -24.87mA   -26.44mA   -20.64mA
1.792V    -24.65mA   -26.47mA   -19.98mA
1.962V    -23.58mA   -24.85mA   -18.66mA
2.098V    -20.94mA   -18.81mA   -17.38mA
2.2V      -14.29mA   -13.11mA   -14.03mA
[GND_clamp]
|Voltage   I(typ)   I(min)   I(max)
-1.1V     -68.65mA   -82.91mA   -64.16mA
-1.054V   -51.26mA   -62.87mA   -50.37mA
-1.008V   -39.63mA   -47.13mA   -42.26mA
-962mV    -32.34mA   -35.82mA   -36.73mA
-916mV    -27.28mA   -28.13mA   -32.02mA
-847mV    -21.22mA   -20.63mA   -25.4mA
-778mV    -15.81mA   -15.27mA   -19.09mA
-663mV    -7.926mA   -8.201mA   -9.607mA
-571mV    -3.246mA   -3.982mA   -3.828mA
-502mV    -1.097mA   -1.819mA   -1.164mA
-410mV    -96.97uA   -374.9uA   -57.53uA
1.1V      0A         0A         0A
[POWER_clamp]
|Voltage   I(typ)   I(min)   I(max)
-1.085V   71.41mA    95.35mA    58.18mA
-1.062V   59.23mA    82.55mA    46.99mA
-1.039V   48.36mA    70.56mA    37.71mA
-1.016V   38.97mA    59.53mA    30.53mA
-970mV    25.17mA    40.76mA    21.88mA
-924mV    17.37mA    26.93mA    17.87mA
-901mV    15.03mA    21.86mA    16.59mA
-855mV    12.01mA    14.79mA    14.5mA
-763mV    8.448mA    8.108mA    10.89mA
-533mV    2.369mA    2.267mA    3.272mA
-349mV    143.9uA    291.4uA    171.3uA
1.1V      0A         0A         0A
[Ramp]
| variable   typ   min   max
dV/dt_r   0.336/0.141n   0.330/0.160n   0.323/0.140n
dV/dt_f   0.402/95.503p   0.393/0.124n   0.404/82.312p
R_load = 50.000
[Rising Waveform]
R_fixture= 50.000
V_fixture= 0.0
V_fixture_min= 0.0
V_fixture_max= 0.0
|time   V(typ)   V(min)   V(max)
0s        961.4nV    5.179uV    441nV
365ps     70.27uV    40.75uV    4.739mV
471ps     7.975mV    -292.4uV   248mV
560ps     200.4mV    4.885mV    431mV
638ps     394.2mV    118.9mV    498.4mV
693ps     478.3mV    245.9mV    518.2mV
795ps     537.7mV    441.8mV    532.2mV
915ps     554.6mV    522.8mV    536.3mV
1.443ns   559.5mV    549mV      537.5mV
10ns      559.5mV    549.2mV    537.6mV
[Rising Waveform]
R_fixture= 50.000
V_fixture= 0.550
V_fixture_min= 0.534
V_fixture_max= 0.568
|time   V(typ)   V(min)   V(max)
0s        214.4mV    206.4mV    229.1mV
366ps     214.5mV    206.4mV    231.3mV
474ps     221.2mV    206mV      526.4mV
543ps     372.4mV    205.8mV    720.6mV
607ps     592mV      257.1mV    801mV
677ps     747.9mV    435.1mV    831.9mV
772ps     814.8mV    679.7mV    844.6mV
892ps     832.9mV    786.6mV    848.2mV
1.142ns   837.1mV    812.2mV    849mV
10ns      837.4mV    813.9mV    849.1mV
[Falling Waveform]
R_fixture= 50.000
V_fixture= 0.550
V_fixture_min= 0.534
V_fixture_max= 0.568
|time   V(typ)   V(min)   V(max)
0s        837.4mV    813.9mV    849.1mV
379ps     837.9mV    813.9mV    844.6mV
403ps     838.9mV    814.1mV    781.3mV
478ps     832.7mV    815.7mV    392.6mV
515ps     750.6mV    817.1mV    308.2mV
595ps     384.1mV    780.4mV    248.8mV
697ps     244mV      445.9mV    233.6mV
807ps     221.5mV    252.6mV    230.3mV
1.077ns   215.1mV    210.1mV    229.2mV
10ns      214.4mV    206.4mV    229.1mV
[Falling Waveform]
R_fixture= 50.000
V_fixture= 0.0
V_fixture_min= 0.0
V_fixture_max= 0.0
|time   V(typ)   V(min)   V(max)
0s        559.5mV    549.2mV    537.5mV
373ps     560.5mV    549.3mV    534.1mV
395ps     561.5mV    549.5mV    481.7mV
484ps     535.6mV    552.3mV    103.4mV
557ps     234.6mV    543.3mV    25mV
595ps     112.8mV    491.6mV    12.94mV
637ps     49.49mV    356.1mV    6.62mV
708ps     14.53mV    123.2mV    2.366mV
797ps     4.131mV    25.82mV    784.1uV
10ns      945.4nV    5.157uV    427.7nV
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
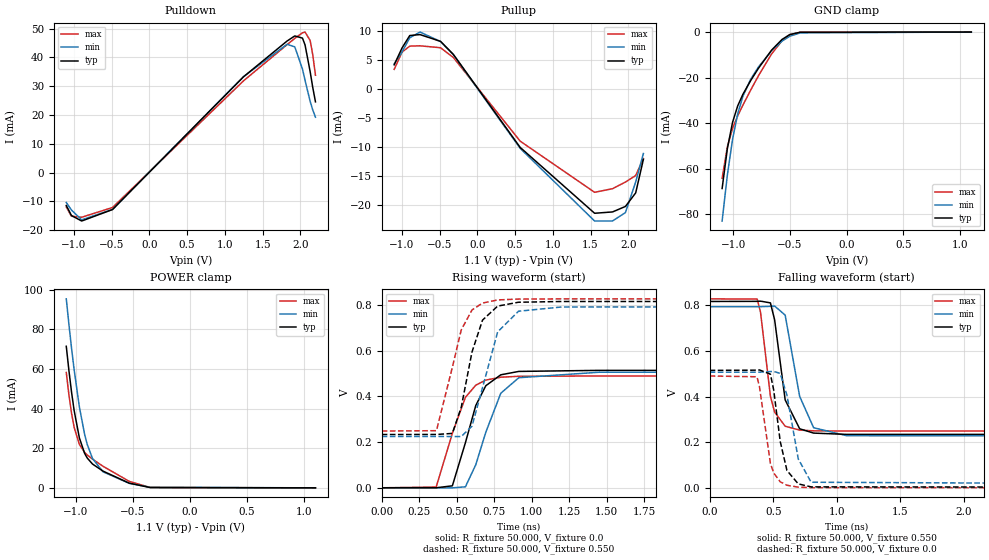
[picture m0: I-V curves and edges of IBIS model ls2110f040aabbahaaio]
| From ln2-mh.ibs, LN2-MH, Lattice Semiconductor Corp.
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|   Model ls2110f040aabbahaaio
[Model] ls2110f040aabbahaaio
| Clamp models do not include dynamic input termination. Please refer to
| the ls2110axxxaabbahaain model for input termination.
Model_type I/O
Polarity   Non-Inverting
Enable   Active-Low
Vinl =  0.200V
Vinh =  0.300V
Vmeas =  0.550V
Cref =  20.000pF
Rref =  50.000
Vref =  0.600V
C_comp   2.000pF   1.500pF   2.500pF
[Temperature Range]   25.000   0.125k   -40.000
[Voltage Range]   1.100V   1.070V   1.130V
[C Comp Corner]
C_comp   2.000pF   1.500pF   2.500pF
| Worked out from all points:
|   slope of the pulldown table from 0 to 0.165 V, typ, clamps not added: 36.9 ohm
|   slope of the pullup table from 0 to 0.165 V, typ, clamps not added: 52.6 ohm
|   GND clamp passes 1 mA (typ) near -0.50 V on its own axis
|   POWER clamp passes 1 mA (typ) near -0.45 V on its own axis
|   rising waveform, R_fixture 50.000, V_fixture 0.0: 20-80 % time 139ps typ, 158ps min, 141ps max; typ from 0 V to 0.515 V
|   rising waveform, R_fixture 50.000, V_fixture 0.550: 20-80 % time 118ps typ, 134ps min, 118ps max; typ from 0.233 V to 0.816 V
|   falling waveform, R_fixture 50.000, V_fixture 0.550: 20-80 % time 89.6ps typ, 113ps min, 80.7ps max; typ from 0.816 V to 0.233 V
|   falling waveform, R_fixture 50.000, V_fixture 0.0: 20-80 % time 83.9ps typ, 102ps min, 78.2ps max; typ from 0.515 V to 0 V
[Pulldown]
|Voltage   I(typ)   I(min)   I(max)
-1.1V     -11.44mA   -10.41mA   -11.96mA
-1.032V   -14.92mA   -13.01mA   -15.18mA
-896mV    -16.84mA   -16.44mA   -15.53mA
-488mV    -12.86mA   -12.79mA   -12.15mA
1.246V    33.22mA    33.26mA    31.81mA
1.824V    45.66mA    44.54mA    44.41mA
1.926V    47.43mA    43.65mA    46.57mA
2.028V    46.68mA    35.94mA    48.54mA
2.062V    44.32mA    32.03mA    48.79mA
2.13V     35mA       24.68mA    45.83mA
2.164V    29.56mA    21.75mA    40.94mA
2.2V      24.55mA    19.2mA     33.8mA
[Pullup]
|Voltage   I(typ)   I(min)   I(max)
-1.1V     4.135mA    4.293mA    3.355mA
-996mV    7.03mA     6.335mA    6.319mA
-894mV    9.159mA    8.781mA    7.344mA
-758mV    9.324mA    9.763mA    7.4mA
-486mV    8.157mA    8.13mA     7.064mA
-316mV    5.917mA    5.851mA    5.381mA
568mV     -10.04mA   -10.2mA    -8.966mA
1.554V    -21.35mA   -22.68mA   -17.75mA
1.792V    -21.12mA   -22.67mA   -17.13mA
1.962V    -20.18mA   -21.24mA   -15.99mA
2.098V    -17.86mA   -15.98mA   -14.88mA
2.2V      -12.11mA   -11.1mA    -11.96mA
[GND_clamp]
|Voltage   I(typ)   I(min)   I(max)
-1.1V     -68.65mA   -82.91mA   -64.16mA
-1.054V   -51.26mA   -62.87mA   -50.37mA
-1.008V   -39.63mA   -47.13mA   -42.26mA
-962mV    -32.34mA   -35.82mA   -36.73mA
-916mV    -27.28mA   -28.13mA   -32.02mA
-847mV    -21.22mA   -20.63mA   -25.4mA
-778mV    -15.81mA   -15.27mA   -19.09mA
-663mV    -7.926mA   -8.201mA   -9.607mA
-571mV    -3.246mA   -3.982mA   -3.828mA
-502mV    -1.097mA   -1.819mA   -1.164mA
-410mV    -96.97uA   -374.9uA   -57.53uA
1.1V      0A         0A         0A
[POWER_clamp]
|Voltage   I(typ)   I(min)   I(max)
-1.085V   71.41mA    95.35mA    58.18mA
-1.062V   59.23mA    82.55mA    46.99mA
-1.039V   48.36mA    70.56mA    37.71mA
-1.016V   38.97mA    59.53mA    30.53mA
-970mV    25.17mA    40.76mA    21.88mA
-924mV    17.37mA    26.93mA    17.87mA
-901mV    15.03mA    21.86mA    16.59mA
-855mV    12.01mA    14.79mA    14.5mA
-763mV    8.448mA    8.108mA    10.89mA
-533mV    2.369mA    2.267mA    3.272mA
-349mV    143.9uA    291.4uA    171.3uA
1.1V      0A         0A         0A
[Ramp]
| variable   typ   min   max
dV/dt_r   0.309/0.139n   0.304/0.159n   0.294/0.141n
dV/dt_f   0.379/97.878p   0.371/0.128n   0.381/84.736p
R_load = 50.000
[Rising Waveform]
R_fixture= 50.000
V_fixture= 0.0
V_fixture_min= 0.0
V_fixture_max= 0.0
|time   V(typ)   V(min)   V(max)
0s        1.068uV    5.74uV     488.6nV
363ps     72.56uV    45.45uV    3.335mV
471ps     8.571mV    -271.7uV   238.7mV
558ps     197.4mV    4.191mV    396.2mV
627ps     360.3mV    100.7mV    449.5mV
694ps     447.2mV    243.4mV    471.9mV
794ps     495mV      414.3mV    484.5mV
914ps     509.9mV    482.3mV    488.6mV
1.449ns   514.5mV    506.3mV    489.9mV
10ns      514.6mV    506.5mV    490mV
[Rising Waveform]
R_fixture= 50.000
V_fixture= 0.550
V_fixture_min= 0.534
V_fixture_max= 0.568
|time   V(typ)   V(min)   V(max)
0s        233.5mV    224.9mV    248.7mV
365ps     233.6mV    225mV      250.2mV
471ps     238.2mV    224.6mV    528mV
530ps     352.2mV    224.4mV    691.4mV
602ps     595.1mV    270mV      779.2mV
672ps     734.6mV    438.7mV    809.5mV
773ps     796.1mV    682.9mV    823.1mV
912ps     813mV      773.7mV    826.9mV
1.201ns   816.3mV    792.4mV    827.7mV
10ns      816.5mV    793.4mV    827.8mV
[Falling Waveform]
R_fixture= 50.000
V_fixture= 0.550
V_fixture_min= 0.534
V_fixture_max= 0.568
|time   V(typ)   V(min)   V(max)
0s        816.4mV    793.4mV    827.8mV
374ps     816.9mV    793.4mV    826.9mV
400ps     817.8mV    793.6mV    770.1mV
478ps     810.2mV    795.1mV    400.7mV
511ps     736.2mV    796.4mV    331.9mV
594ps     385.3mV    756.6mV    269.9mV
708ps     258.7mV    400.3mV    252.9mV
818ps     239.8mV    263.3mV    249.8mV
1.078ns   234.1mV    228.3mV    248.8mV
10ns      233.5mV    224.9mV    248.7mV
[Falling Waveform]
R_fixture= 50.000
V_fixture= 0.0
V_fixture_min= 0.0
V_fixture_max= 0.0
|time   V(typ)   V(min)   V(max)
0s        514.6mV    506.5mV    489.9mV
372ps     515.5mV    506.6mV    486.6mV
392ps     516.4mV    506.8mV    442.6mV
478ps     498.1mV    509.3mV    106.3mV
504ps     427.7mV    510mV      65.03mV
555ps     203.4mV    501mV      26.45mV
608ps     75.95mV    406mV      11.23mV
697ps     17.29mV    126.7mV    3.04mV
798ps     4.286mV    24.61mV    837.3uV
10ns      1.052uV    5.719uV    474.5nV
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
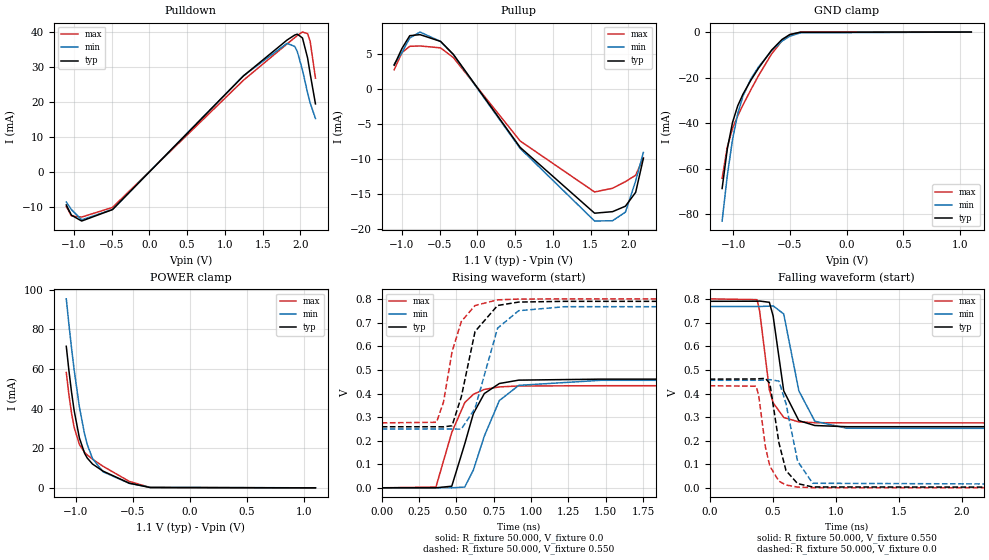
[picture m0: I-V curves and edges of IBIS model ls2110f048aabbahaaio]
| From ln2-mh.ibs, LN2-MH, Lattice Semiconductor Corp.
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|   Model ls2110f048aabbahaaio
[Model] ls2110f048aabbahaaio
| Clamp models do not include dynamic input termination. Please refer to
| the ls2110axxxaabbahaain model for input termination.
Model_type I/O
Polarity   Non-Inverting
Enable   Active-Low
Vinl =  0.200V
Vinh =  0.300V
Vmeas =  0.550V
Cref =  20.000pF
Rref =  50.000
Vref =  0.600V
C_comp   2.000pF   1.500pF   2.500pF
[Temperature Range]   25.000   0.125k   -40.000
[Voltage Range]   1.100V   1.070V   1.130V
[C Comp Corner]
C_comp   2.000pF   1.500pF   2.500pF
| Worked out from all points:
|   slope of the pulldown table from 0 to 0.165 V, typ, clamps not added: 44.4 ohm
|   slope of the pullup table from 0 to 0.165 V, typ, clamps not added: 63.1 ohm
|   GND clamp passes 1 mA (typ) near -0.50 V on its own axis
|   POWER clamp passes 1 mA (typ) near -0.45 V on its own axis
|   rising waveform, R_fixture 50.000, V_fixture 0.0: 20-80 % time 135ps typ, 160ps min, 131ps max; typ from 0 V to 0.461 V
|   rising waveform, R_fixture 50.000, V_fixture 0.550: 20-80 % time 112ps typ, 134ps min, 107ps max; typ from 0.259 V to 0.791 V
|   falling waveform, R_fixture 50.000, V_fixture 0.550: 20-80 % time 95.3ps typ, 123ps min, 83ps max; typ from 0.791 V to 0.259 V
|   falling waveform, R_fixture 50.000, V_fixture 0.0: 20-80 % time 88.5ps typ, 109ps min, 81.1ps max; typ from 0.461 V to 0 V
[Pulldown]
|Voltage   I(typ)   I(min)   I(max)
-1.1V     -9.331mA   -8.492mA   -9.729mA
-1.032V   -12.24mA   -10.65mA   -12.45mA
-896mV    -13.91mA   -13.57mA   -12.78mA
-488mV    -10.65mA   -10.6mA    -10.03mA
1.246V    27.54mA    27.59mA    26.3mA
1.824V    37.8mA     36.87mA    36.7mA
1.926V    39.24mA    35.96mA    38.49mA
1.96V     39.48mA    34.49mA    39.08mA
2.028V    38.4mA     29.21mA    40.09mA
2.096V    32.66mA    22.68mA    39.63mA
2.13V     28.15mA    19.83mA    37.42mA
2.2V      19.56mA    15.36mA    26.91mA
[Pullup]
|Voltage   I(typ)   I(min)   I(max)
-1.1V     3.391mA    3.517mA    2.749mA
-996mV    5.814mA    5.23mA     5.224mA
-894mV    7.622mA    7.298mA    6.097mA
-758mV    7.769mA    8.144mA    6.15mA
-486mV    6.803mA    6.791mA    5.876mA
-316mV    4.941mA    4.892mA    4.481mA
568mV     -8.372mA   -8.524mA   -7.458mA
1.554V    -17.8mA    -18.92mA   -14.76mA
1.792V    -17.58mA   -18.88mA   -14.23mA
1.962V    -16.8mA    -17.66mA   -13.28mA
2.098V    -14.81mA   -13.18mA   -12.36mA
2.2V      -9.957mA   -9.113mA   -9.868mA
[GND_clamp]
|Voltage   I(typ)   I(min)   I(max)
-1.1V     -68.65mA   -82.91mA   -64.16mA
-1.054V   -51.26mA   -62.87mA   -50.37mA
-1.008V   -39.63mA   -47.13mA   -42.26mA
-962mV    -32.34mA   -35.82mA   -36.73mA
-916mV    -27.28mA   -28.13mA   -32.02mA
-847mV    -21.22mA   -20.63mA   -25.4mA
-778mV    -15.81mA   -15.27mA   -19.09mA
-663mV    -7.926mA   -8.201mA   -9.607mA
-571mV    -3.246mA   -3.982mA   -3.828mA
-502mV    -1.097mA   -1.819mA   -1.164mA
-410mV    -96.97uA   -374.9uA   -57.53uA
1.1V      0A         0A         0A
[POWER_clamp]
|Voltage   I(typ)   I(min)   I(max)
-1.085V   71.41mA    95.35mA    58.18mA
-1.062V   59.23mA    82.55mA    46.99mA
-1.039V   48.36mA    70.56mA    37.71mA
-1.016V   38.97mA    59.53mA    30.53mA
-970mV    25.17mA    40.76mA    21.88mA
-924mV    17.37mA    26.93mA    17.87mA
-901mV    15.03mA    21.86mA    16.59mA
-855mV    12.01mA    14.79mA    14.5mA
-763mV    8.448mA    8.108mA    10.89mA
-533mV    2.369mA    2.267mA    3.272mA
-349mV    143.9uA    291.4uA    171.3uA
1.1V      0A         0A         0A
[Ramp]
| variable   typ   min   max
dV/dt_r   0.277/0.135n   0.274/0.160n   0.260/0.131n
dV/dt_f   0.349/0.105n   0.341/0.141n   0.349/86.649p
R_load = 50.000
[Rising Waveform]
R_fixture= 50.000
V_fixture= 0.0
V_fixture_min= 0.0
V_fixture_max= 0.0
|time   V(typ)   V(min)   V(max)
0s        1.208uV    6.471uV    552nV
363ps     79.37uV    53.02uV    3.213mV
469ps     6.722mV    -233.4uV   234.7mV
556ps     186.2mV    3.224mV    361.3mV
614ps     315.4mV    75.74mV    396.8mV
687ps     399.8mV    219.2mV    417.4mV
788ps     442.5mV    370.2mV    428.1mV
918ps     456.8mV    434.6mV    431.9mV
1.468ns   461mV      456.1mV    433.1mV
10ns      461.1mV    456.3mV    433.1mV
[Rising Waveform]
R_fixture= 50.000
V_fixture= 0.550
V_fixture_min= 0.534
V_fixture_max= 0.568
|time   V(typ)   V(min)   V(max)
0s        258.9mV    249.5mV    275.5mV
367ps     259mV      249.5mV    277.9mV
414ps     258.5mV    249.5mV    364.3mV
471ps     263.4mV    249.2mV    577.1mV
533ps     386mV      248.9mV    705.4mV
625ps     663.2mV    337.2mV    773.4mV
776ps     773.5mV    677.2mV    797.4mV
917ps     788mV      751.4mV    800.7mV
1.226ns   791.1mV    768.4mV    801.5mV
10ns      791.2mV    769.2mV    801.6mV
[Falling Waveform]
R_fixture= 50.000
V_fixture= 0.550
V_fixture_min= 0.534
V_fixture_max= 0.568
|time   V(typ)   V(min)   V(max)
0s        791.2mV    769.2mV    801.6mV
376ps     791.7mV    769.2mV    798.3mV
396ps     792.4mV    769.3mV    753mV
474ps     787.1mV    770.7mV    416.2mV
504ps     728.4mV    771.9mV    360.7mV
588ps     411.2mV    737.6mV    298.5mV
708ps     285.1mV    411.6mV    279.7mV
835ps     264.4mV    282.6mV    276.4mV
1.088ns   259.4mV    252.8mV    275.6mV
10ns      258.9mV    249.5mV    275.5mV
[Falling Waveform]
R_fixture= 50.000
V_fixture= 0.0
V_fixture_min= 0.0
V_fixture_max= 0.0
|time   V(typ)   V(min)   V(max)
0s        461.1mV    456.3mV    433.1mV
370ps     461.9mV    456.3mV    431.1mV
390ps     462.8mV    456.5mV    389.3mV
443ps     464.2mV    457.6mV    171.6mV
478ps     442.9mV    459mV      91.87mV
550ps     190.8mV    452.7mV    28.14mV
606ps     73.33mV    356.9mV    12.07mV
698ps     17.96mV    113mV      3.3mV
818ps     3.725mV    19.46mV    726uV
10ns      1.191uV    6.451uV    537.2nV
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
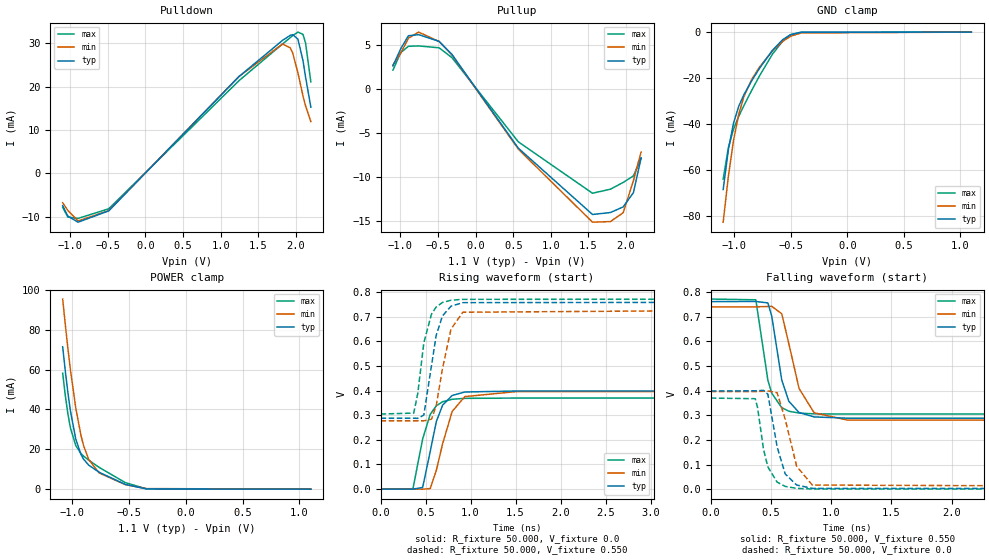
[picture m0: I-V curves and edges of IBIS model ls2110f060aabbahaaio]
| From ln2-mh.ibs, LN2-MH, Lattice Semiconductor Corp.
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|   Model ls2110f060aabbahaaio
[Model] ls2110f060aabbahaaio
| Clamp models do not include dynamic input termination. Please refer to
| the ls2110axxxaabbahaain model for input termination.
Model_type I/O
Polarity   Non-Inverting
Enable   Active-Low
Vinl =  0.200V
Vinh =  0.300V
Vmeas =  0.550V
Cref =  20.000pF
Rref =  50.000
Vref =  0.600V
C_comp   2.000pF   1.500pF   2.500pF
[Temperature Range]   25.000   0.125k   -40.000
[Voltage Range]   1.100V   1.070V   1.130V
[C Comp Corner]
C_comp   2.000pF   1.500pF   2.500pF
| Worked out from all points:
|   slope of the pulldown table from 0 to 0.165 V, typ, clamps not added: 54.8 ohm
|   slope of the pullup table from 0 to 0.165 V, typ, clamps not added: 78.5 ohm
|   GND clamp passes 1 mA (typ) near -0.50 V on its own axis
|   POWER clamp passes 1 mA (typ) near -0.45 V on its own axis
|   rising waveform, R_fixture 50.000, V_fixture 0.0: 20-80 % time 146ps typ, 176ps min, 138ps max; typ from 0 V to 0.398 V
|   rising waveform, R_fixture 50.000, V_fixture 0.550: 20-80 % time 121ps typ, 144ps min, 115ps max; typ from 0.288 V to 0.762 V
|   falling waveform, R_fixture 50.000, V_fixture 0.550: 20-80 % time 107ps typ, 138ps min, 91.7ps max; typ from 0.762 V to 0.288 V
|   falling waveform, R_fixture 50.000, V_fixture 0.0: 20-80 % time 97.8ps typ, 121ps min, 88.3ps max; typ from 0.398 V to 0 V
[Pulldown]
|Voltage   I(typ)   I(min)   I(max)
-1.1V     -7.434mA   -6.752mA   -7.793mA
-1.032V   -9.813mA   -8.512mA   -10.05mA
-896mV    -11.23mA   -10.93mA   -10.36mA
-488mV    -8.626mA   -8.574mA   -8.147mA
1.246V    22.32mA    22.34mA    21.37mA
1.824V    30.63mA    29.8mA     29.8mA
1.926V    31.78mA    28.92mA    31.25mA
1.96V     31.94mA    27.63mA    31.73mA
2.028V    30.91mA    23.16mA    32.53mA
2.096V    25.92mA    17.81mA    32mA
2.13V     22.15mA    15.51mA    29.99mA
2.2V      15.25mA    11.94mA    21.05mA
[Pullup]
|Voltage   I(typ)   I(min)   I(max)
-1.1V     2.659mA    2.739mA    2.174mA
-996mV    4.615mA    4.123mA    4.178mA
-894mV    6.091mA    5.806mA    4.892mA
-758mV    6.217mA    6.508mA    4.932mA
-486mV    5.452mA    5.436mA    4.716mA
-316mV    3.967mA    3.921mA    3.605mA
568mV     -6.721mA   -6.835mA   -6mA
1.554V    -14.27mA   -15.15mA   -11.85mA
1.792V    -14.05mA   -15.08mA   -11.39mA
1.962V    -13.41mA   -14.07mA   -10.62mA
2.098V    -11.78mA   -10.42mA   -9.872mA
2.2V      -7.847mA   -7.155mA   -7.839mA
[GND_clamp]
|Voltage   I(typ)   I(min)   I(max)
-1.1V     -68.65mA   -82.91mA   -64.16mA
-1.054V   -51.26mA   -62.87mA   -50.37mA
-1.008V   -39.63mA   -47.13mA   -42.26mA
-962mV    -32.34mA   -35.82mA   -36.73mA
-916mV    -27.28mA   -28.13mA   -32.02mA
-847mV    -21.22mA   -20.63mA   -25.4mA
-778mV    -15.81mA   -15.27mA   -19.09mA
-663mV    -7.926mA   -8.201mA   -9.607mA
-571mV    -3.246mA   -3.982mA   -3.828mA
-502mV    -1.097mA   -1.819mA   -1.164mA
-410mV    -96.97uA   -374.9uA   -57.53uA
1.1V      0A         0A         0A
[POWER_clamp]
|Voltage   I(typ)   I(min)   I(max)
-1.085V   71.41mA    95.35mA    58.18mA
-1.062V   59.23mA    82.55mA    46.99mA
-1.039V   48.36mA    70.56mA    37.71mA
-1.016V   38.97mA    59.53mA    30.53mA
-970mV    25.17mA    40.76mA    21.88mA
-924mV    17.37mA    26.93mA    17.87mA
-901mV    15.03mA    21.86mA    16.59mA
-855mV    12.01mA    14.79mA    14.5mA
-763mV    8.448mA    8.108mA    10.89mA
-533mV    2.369mA    2.267mA    3.272mA
-349mV    143.9uA    291.4uA    171.3uA
1.1V      0A         0A         0A
[Ramp]
| variable   typ   min   max
dV/dt_r   0.239/0.146n   0.238/0.176n   0.222/0.138n
dV/dt_f   0.314/0.118n   0.307/0.159n   0.314/96.206p
R_load = 50.000
[Rising Waveform]
R_fixture= 50.000
V_fixture= 0.0
V_fixture_min= 0.0
V_fixture_max= 0.0
|time   V(typ)   V(min)   V(max)
0s        1.37uV     7.322uV    623.3nV
360ps     81.53uV    62.32uV    1.585mV
468ps     6.831mV    -195.9uV   203.7mV
552ps     153mV      2.273mV    303.9mV
620ps     274.8mV    76.19mV    338.5mV
690ps     341.1mV    184.9mV    355mV
796ps     380.4mV    315.6mV    364.9mV
936ps     394.4mV    375.7mV    368.6mV
1.516ns   398.4mV    396.3mV    369.8mV
10ns      398.5mV    396.5mV    369.8mV
[Rising Waveform]
R_fixture= 50.000
V_fixture= 0.550
V_fixture_min= 0.534
V_fixture_max= 0.568
|time   V(typ)   V(min)   V(max)
0s        287.8mV    277.7mV    304.9mV
369ps     287.9mV    277.7mV    308.7mV
414ps     287.5mV    277.7mV    389.6mV
481ps     300.8mV    277.3mV    594.4mV
566ps     501.3mV    284.1mV    710.7mV
618ps     623.9mV    337.3mV    739.5mV
688ps     703.5mV    489.7mV    757.8mV
783ps     742.8mV    650mV      767.1mV
914ps     757.2mV    718.3mV    770.7mV
10ns      761.5mV    740.2mV    771.8mV
[Falling Waveform]
R_fixture= 50.000
V_fixture= 0.550
V_fixture_min= 0.534
V_fixture_max= 0.568
|time   V(typ)   V(min)   V(max)
0s        761.5mV    740.2mV    771.8mV
374ps     762mV      740.2mV    768.8mV
474ps     756.2mV    741.6mV    442.4mV
506ps     703.2mV    742.4mV    389.9mV
589ps     443.7mV    712.4mV    330.8mV
648ps     356.9mV    590.8mV    316.5mV
733ps     311.1mV    408.6mV    308.8mV
858ps     293.3mV    310.1mV    305.8mV
1.133ns   288.2mV    280.7mV    305mV
10ns      287.8mV    277.6mV    304.9mV
[Falling Waveform]
R_fixture= 50.000
V_fixture= 0.0
V_fixture_min= 0.0
V_fixture_max= 0.0
|time   V(typ)   V(min)   V(max)
0s        398.5mV    396.5mV    369.8mV
369ps     399.3mV    396.5mV    367.3mV
388ps     400mV      396.6mV    332.5mV
438ps     401.2mV    397.5mV    161mV
474ps     385.3mV    398.8mV    90.24mV
551ps     171.2mV    391.6mV    28.52mV
618ps     61.83mV    283.3mV    11.21mV
713ps     16.69mV    92.86mV    3.216mV
843ps     3.402mV    16.74mV    676.8uV
10ns      1.353uV    7.305uV    607.7nV
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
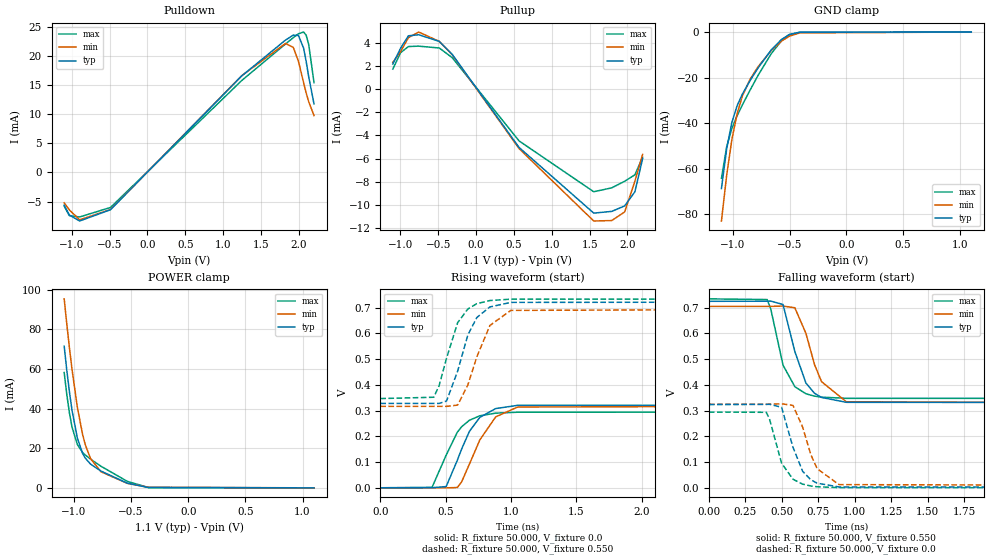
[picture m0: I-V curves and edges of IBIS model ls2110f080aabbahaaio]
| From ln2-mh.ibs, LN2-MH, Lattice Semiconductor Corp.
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|   Model ls2110f080aabbahaaio
[Model] ls2110f080aabbahaaio
| Clamp models do not include dynamic input termination. Please refer to
| the ls2110axxxaabbahaain model for input termination.
Model_type I/O
Polarity   Non-Inverting
Enable   Active-Low
Vinl =  0.200V
Vinh =  0.300V
Vmeas =  0.550V
Cref =  20.000pF
Rref =  50.000
Vref =  0.600V
C_comp   2.000pF   1.500pF   2.500pF
[Temperature Range]   25.000   0.125k   -40.000
[Voltage Range]   1.100V   1.070V   1.130V
[C Comp Corner]
C_comp   2.000pF   1.500pF   2.500pF
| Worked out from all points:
|   slope of the pulldown table from 0 to 0.165 V, typ, clamps not added: 73.8 ohm
|   slope of the pullup table from 0 to 0.165 V, typ, clamps not added: 104 ohm
|   GND clamp passes 1 mA (typ) near -0.50 V on its own axis
|   POWER clamp passes 1 mA (typ) near -0.45 V on its own axis
|   rising waveform, R_fixture 50.000, V_fixture 0.0: 20-80 % time 175ps typ, 192ps min, 168ps max; typ from 0 V to 0.324 V
|   rising waveform, R_fixture 50.000, V_fixture 0.550: 20-80 % time 152ps typ, 168ps min, 142ps max; typ from 0.328 V to 0.725 V
|   falling waveform, R_fixture 50.000, V_fixture 0.550: 20-80 % time 120ps typ, 140ps min, 110ps max; typ from 0.725 V to 0.328 V
|   falling waveform, R_fixture 50.000, V_fixture 0.0: 20-80 % time 111ps typ, 123ps min, 103ps max; typ from 0.324 V to 0 V
[Pulldown]
|Voltage   I(typ)   I(min)   I(max)
-1.1V     -5.63mA    -5.217mA   -5.79mA
-1.032V   -7.317mA   -6.439mA   -7.425mA
-896mV    -8.348mA   -8.148mA   -7.654mA
-488mV    -6.408mA   -6.379mA   -6.018mA
1.246V    16.59mA    16.63mA    15.8mA
1.824V    22.74mA    22.16mA    22.07mA
1.926V    23.59mA    21.49mA    23.15mA
1.994V    23.53mA    19.11mA    23.83mA
2.062V    21.38mA    15.45mA    24.12mA
2.096V    19.11mA    13.68mA    23.59mA
2.13V     16.44mA    12.14mA    21.98mA
2.2V      11.76mA    9.772mA    15.43mA
[Pullup]
|Voltage   I(typ)   I(min)   I(max)
-1.1V     2.15mA     2.287mA    1.709mA
-996mV    3.524mA    3.244mA    3.134mA
-894mV    4.58mA     4.417mA    3.654mA
-758mV    4.67mA     4.905mA    3.687mA
-486mV    4.097mA    4.096mA    3.528mA
-316mV    2.983mA    2.956mA    2.698mA
568mV     -5.048mA   -5.147mA   -4.484mA
1.554V    -10.71mA   -11.39mA   -8.866mA
1.792V    -10.56mA   -11.35mA   -8.53mA
1.962V    -10.09mA   -10.61mA   -7.964mA
2.098V    -8.866mA   -7.952mA   -7.404mA
2.2V      -6.01mA    -5.644mA   -5.887mA
[GND_clamp]
|Voltage   I(typ)   I(min)   I(max)
-1.1V     -68.65mA   -82.91mA   -64.16mA
-1.054V   -51.26mA   -62.87mA   -50.37mA
-1.008V   -39.63mA   -47.13mA   -42.26mA
-962mV    -32.34mA   -35.82mA   -36.73mA
-916mV    -27.28mA   -28.13mA   -32.02mA
-847mV    -21.22mA   -20.63mA   -25.4mA
-778mV    -15.81mA   -15.27mA   -19.09mA
-663mV    -7.926mA   -8.201mA   -9.607mA
-571mV    -3.246mA   -3.982mA   -3.828mA
-502mV    -1.097mA   -1.819mA   -1.164mA
-410mV    -96.97uA   -374.9uA   -57.53uA
1.1V      0A         0A         0A
[POWER_clamp]
|Voltage   I(typ)   I(min)   I(max)
-1.085V   71.41mA    95.35mA    58.18mA
-1.062V   59.23mA    82.55mA    46.99mA
-1.039V   48.36mA    70.56mA    37.71mA
-1.016V   38.97mA    59.53mA    30.53mA
-970mV    25.17mA    40.76mA    21.88mA
-924mV    17.37mA    26.93mA    17.87mA
-901mV    15.03mA    21.86mA    16.59mA
-855mV    12.01mA    14.79mA    14.5mA
-763mV    8.448mA    8.108mA    10.89mA
-533mV    2.369mA    2.267mA    3.272mA
-349mV    143.9uA    291.4uA    171.3uA
1.1V      0A         0A         0A
[Ramp]
| variable   typ   min   max
dV/dt_r   0.194/0.175n   0.195/0.192n   0.177/0.168n
dV/dt_f   0.266/0.132n   0.261/0.162n   0.264/0.119n
R_load = 50.000
[Rising Waveform]
R_fixture= 50.000
V_fixture= 0.0
V_fixture_min= 0.0
V_fixture_max= 0.0
|time   V(typ)   V(min)   V(max)
0s        1.59uV     8.481uV    722.6nV
396ps     167.6uV    121.5uV    1.623mV
504ps     4.629mV    -304.6uV   126.7mV
589ps     106.2mV    993uV      215.6mV
622ps     149.9mV    22.42mV    237mV
682ps     219.3mV    91.96mV    262.4mV
762ps     273.8mV    186.2mV    279.9mV
883ps     307.9mV    275.5mV    290.1mV
1.052ns   320.5mV    314mV      293.7mV
10ns      323.6mV    325mV      294.6mV
[Rising Waveform]
R_fixture= 50.000
V_fixture= 0.550
V_fixture_min= 0.534
V_fixture_max= 0.568
|time   V(typ)   V(min)   V(max)
0s        328mV      316.5mV    346.8mV
409ps     327.9mV    316.6mV    351.9mV
450ps     327.8mV    316.7mV    396.9mV
507ps     337.3mV    316.4mV    503.9mV
592ps     453.5mV    321.5mV    641.7mV
670ps     594mV      399.5mV    694.9mV
739ps     662mV      509.2mV    715.7mV
839ps     703mV      631mV      728mV
999ps     720.7mV    689.6mV    733.2mV
10ns      724.9mV    705.1mV    734.4mV
[Falling Waveform]
R_fixture= 50.000
V_fixture= 0.550
V_fixture_min= 0.534
V_fixture_max= 0.568
|time   V(typ)   V(min)   V(max)
0s        724.9mV    705.1mV    734.4mV
399ps     725.2mV    705.1mV    731.7mV
424ps     725.8mV    705.2mV    694.6mV
508ps     712.4mV    706.4mV    476.6mV
589ps     529.6mV    699.8mV    393mV
665ps     407mV      600mV      365.5mV
724ps     367.5mV    478.7mV    356.4mV
772ps     351.3mV    412.6mV    352.5mV
942ps     332.4mV    334.5mV    347.9mV
10ns      328mV      316.5mV    346.8mV
[Falling Waveform]
R_fixture= 50.000
V_fixture= 0.0
V_fixture_min= 0.0
V_fixture_max= 0.0
|time   V(typ)   V(min)   V(max)
0s        323.6mV    325mV      294.6mV
393ps     324.2mV    325mV      293.5mV
415ps     324.8mV    325.1mV    267.9mV
498ps     313.1mV    326.7mV    96.03mV
576ps     157.8mV    320.5mV    33.39mV
642ps     64.7mV     236.4mV    14.47mV
699ps     30.84mV    128.2mV    7.246mV
742ps     18.21mV    74.29mV    4.391mV
892ps     3.392mV    12.55mV    896.7uV
10ns      1.569uV    8.458uV    705.6nV
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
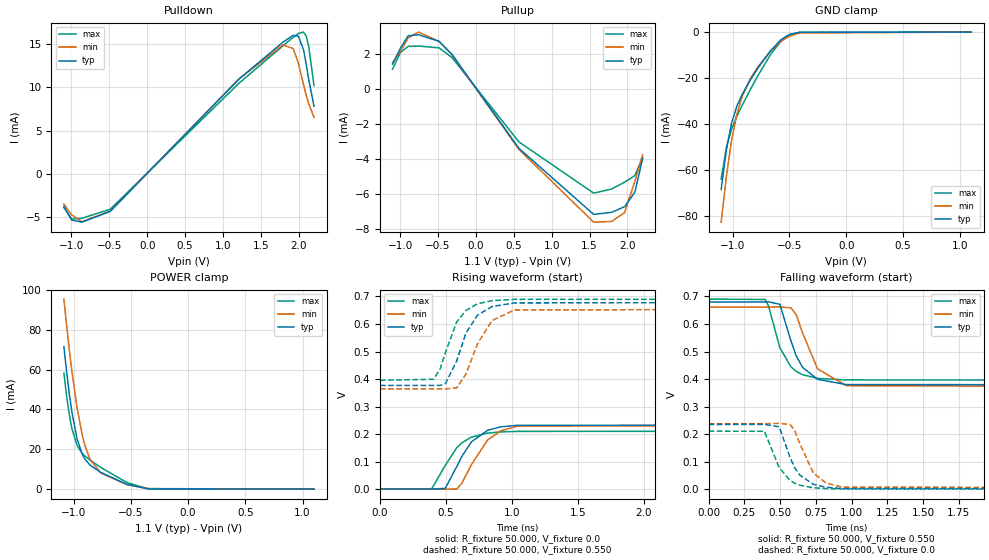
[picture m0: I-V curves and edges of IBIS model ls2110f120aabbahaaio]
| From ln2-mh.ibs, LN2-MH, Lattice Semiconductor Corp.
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|   Model ls2110f120aabbahaaio
[Model] ls2110f120aabbahaaio
| Clamp models do not include dynamic input termination. Please refer to
| the ls2110axxxaabbahaain model for input termination.
Model_type I/O
Polarity   Non-Inverting
Enable   Active-Low
Vinl =  0.200V
Vinh =  0.300V
Vmeas =  0.550V
Cref =  20.000pF
Rref =  50.000
Vref =  0.600V
C_comp   2.000pF   1.500pF   2.500pF
[Temperature Range]   25.000   0.125k   -40.000
[Voltage Range]   1.100V   1.070V   1.130V
[C Comp Corner]
C_comp   2.000pF   1.500pF   2.500pF
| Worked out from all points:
|   slope of the pulldown table from 0 to 0.165 V, typ, clamps not added: 108 ohm
|   slope of the pullup table from 0 to 0.165 V, typ, clamps not added: 156 ohm
|   GND clamp passes 1 mA (typ) near -0.50 V on its own axis
|   POWER clamp passes 1 mA (typ) near -0.45 V on its own axis
|   rising waveform, R_fixture 50.000, V_fixture 0.0: 20-80 % time 179ps typ, 193ps min, 174ps max; typ from 0 V to 0.235 V
|   rising waveform, R_fixture 50.000, V_fixture 0.550: 20-80 % time 156ps typ, 171ps min, 145ps max; typ from 0.377 V to 0.68 V
|   falling waveform, R_fixture 50.000, V_fixture 0.550: 20-80 % time 130ps typ, 146ps min, 123ps max; typ from 0.68 V to 0.377 V
|   falling waveform, R_fixture 50.000, V_fixture 0.0: 20-80 % time 121ps typ, 131ps min, 116ps max; typ from 0.235 V to 0 V
[Pulldown]
|Voltage   I(typ)   I(min)   I(max)
-1.1V     -3.788mA   -3.514mA   -3.915mA
-998mV    -5.355mA   -4.765mA   -5.25mA
-862mV    -5.61mA    -5.559mA   -5.155mA
-488mV    -4.353mA   -4.328mA   -4.108mA
1.212V    10.98mA    11mA       10.5mA
1.79V     15.24mA    14.92mA    14.82mA
1.926V    16.03mA    14.5mA     15.8mA
1.994V    15.95mA    12.81mA    16.26mA
2.062V    14.36mA    10.31mA    16.41mA
2.096V    12.76mA    9.126mA    15.99mA
2.13V     10.93mA    8.106mA    14.77mA
2.2V      7.825mA    6.542mA    10.21mA
[Pullup]
|Voltage   I(typ)   I(min)   I(max)
-1.1V     1.431mA    1.519mA    1.144mA
-996mV    2.344mA    2.153mA    2.098mA
-894mV    3.054mA    2.935mA    2.449mA
-758mV    3.115mA    3.266mA    2.469mA
-486mV    2.737mA    2.731mA    2.364mA
-316mV    1.997mA    1.974mA    1.813mA
568mV     -3.38mA    -3.44mA    -3.014mA
1.554V    -7.157mA   -7.603mA   -5.943mA
1.792V    -7.039mA   -7.561mA   -5.703mA
1.962V    -6.716mA   -7.052mA   -5.316mA
2.098V    -5.883mA   -5.265mA   -4.937mA
2.2V      -3.975mA   -3.74mA    -3.911mA
[GND_clamp]
|Voltage   I(typ)   I(min)   I(max)
-1.1V     -68.65mA   -82.91mA   -64.16mA
-1.054V   -51.26mA   -62.87mA   -50.37mA
-1.008V   -39.63mA   -47.13mA   -42.26mA
-962mV    -32.34mA   -35.82mA   -36.73mA
-916mV    -27.28mA   -28.13mA   -32.02mA
-847mV    -21.22mA   -20.63mA   -25.4mA
-778mV    -15.81mA   -15.27mA   -19.09mA
-663mV    -7.926mA   -8.201mA   -9.607mA
-571mV    -3.246mA   -3.982mA   -3.828mA
-502mV    -1.097mA   -1.819mA   -1.164mA
-410mV    -96.97uA   -374.9uA   -57.53uA
1.1V      0A         0A         0A
[POWER_clamp]
|Voltage   I(typ)   I(min)   I(max)
-1.085V   71.41mA    95.35mA    58.18mA
-1.062V   59.23mA    82.55mA    46.99mA
-1.039V   48.36mA    70.56mA    37.71mA
-1.016V   38.97mA    59.53mA    30.53mA
-970mV    25.17mA    40.76mA    21.88mA
-924mV    17.37mA    26.93mA    17.87mA
-901mV    15.03mA    21.86mA    16.59mA
-855mV    12.01mA    14.79mA    14.5mA
-763mV    8.448mA    8.108mA    10.89mA
-533mV    2.369mA    2.267mA    3.272mA
-349mV    143.9uA    291.4uA    171.3uA
1.1V      0A         0A         0A
[Ramp]
| variable   typ   min   max
dV/dt_r   0.141/0.179n   0.143/0.193n   0.126/0.174n
dV/dt_f   0.207/0.143n   0.203/0.168n   0.205/0.131n
R_load = 50.000
[Rising Waveform]
R_fixture= 50.000
V_fixture= 0.0
V_fixture_min= 0.0
V_fixture_max= 0.0
|time   V(typ)   V(min)   V(max)
0s        1.863uV    9.921uV    840.8nV
392ps     240.5uV    127.3uV    1.595mV
494ps     2.825mV    -85.25uV   86.06mV
582ps     82.82mV    758.9uV    151.1mV
621ps     120.1mV    22.34mV    168.8mV
693ps     172.2mV    89.29mV    189.1mV
814ps     213.6mV    178mV      203.6mV
914ps     226.3mV    211.9mV    207.9mV
1.042ns   232.1mV    229.1mV    209.8mV
10ns      234.9mV    237.8mV    210.7mV
[Rising Waveform]
R_fixture= 50.000
V_fixture= 0.550
V_fixture_min= 0.534
V_fixture_max= 0.568
|time   V(typ)   V(min)   V(max)
0s        376.7mV    364.2mV    395.6mV
406ps     376.8mV    364.3mV    399.1mV
455ps     376.8mV    364.4mV    436.3mV
496ps     383.7mV    364.1mV    497.4mV
581ps     466.2mV    368.1mV    607.4mV
651ps     567.1mV    418.5mV    649.4mV
738ps     631.7mV    527.5mV    673.3mV
848ps     663.4mV    612.6mV    684.8mV
1.018ns   676.7mV    650.9mV    689.5mV
10ns      680mV      661.3mV    690.6mV
[Falling Waveform]
R_fixture= 50.000
V_fixture= 0.550
V_fixture_min= 0.534
V_fixture_max= 0.568
|time   V(typ)   V(min)   V(max)
0s        680mV      661.3mV    690.6mV
396ps     680.2mV    661.3mV    689mV
419ps     680.6mV    661.3mV    664.9mV
498ps     671.6mV    662.2mV    513.8mV
576ps     537.9mV    658.6mV    444.2mV
613ps     483.6mV    633.3mV    428mV
657ps     442.6mV    567mV      415.8mV
762ps     398.9mV    436.9mV    402.4mV
962ps     380.1mV    375.9mV    396.7mV
10ns      376.7mV    364.2mV    395.6mV
[Falling Waveform]
R_fixture= 50.000
V_fixture= 0.0
V_fixture_min= 0.0
V_fixture_max= 0.0
|time   V(typ)   V(min)   V(max)
0s        234.9mV    237.8mV    210.7mV
390ps     235.3mV    237.9mV    210.3mV
493ps     226.7mV    239.1mV    78.77mV
569ps     115.9mV    235.1mV    31.74mV
601ps     78.86mV    214.2mV    21.95mV
638ps     50.78mV    164.7mV    14.48mV
732ps     17.76mV    58.98mV    5.176mV
818ps     7.155mV    23.22mV    2.114mV
931ps     2.334mV    7.464mV    707.6uV
10ns      1.84uV     9.901uV    822.8nV
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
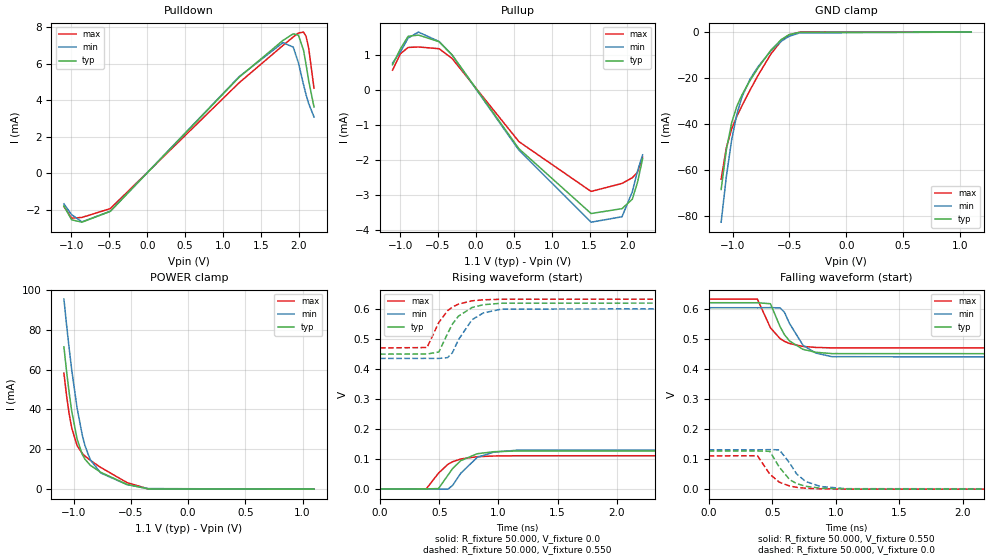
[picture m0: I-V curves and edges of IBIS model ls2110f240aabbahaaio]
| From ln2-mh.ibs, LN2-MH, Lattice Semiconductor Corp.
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|   Model ls2110f240aabbahaaio
[Model] ls2110f240aabbahaaio
| Clamp models do not include dynamic input termination. Please refer to
| the ls2110axxxaabbahaain model for input termination.
Model_type I/O
Polarity   Non-Inverting
Enable   Active-Low
Vinl =  0.200V
Vinh =  0.300V
Vmeas =  0.550V
Cref =  20.000pF
Rref =  50.000
Vref =  0.600V
C_comp   2.000pF   1.500pF   2.500pF
[Temperature Range]   25.000   0.125k   -40.000
[Voltage Range]   1.100V   1.070V   1.130V
[C Comp Corner]
C_comp   2.000pF   1.500pF   2.500pF
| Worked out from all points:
|   slope of the pulldown table from 0 to 0.165 V, typ, clamps not added: 226 ohm
|   slope of the pullup table from 0 to 0.165 V, typ, clamps not added: 313 ohm
|   GND clamp passes 1 mA (typ) near -0.50 V on its own axis
|   POWER clamp passes 1 mA (typ) near -0.45 V on its own axis
|   rising waveform, R_fixture 50.000, V_fixture 0.0: 20-80 % time 170ps typ, 180ps min, 162ps max; typ from 0 V to 0.128 V
|   rising waveform, R_fixture 50.000, V_fixture 0.550: 20-80 % time 157ps typ, 166ps min, 150ps max; typ from 0.451 V to 0.623 V
|   falling waveform, R_fixture 50.000, V_fixture 0.550: 20-80 % time 142ps typ, 155ps min, 136ps max; typ from 0.623 V to 0.451 V
|   falling waveform, R_fixture 50.000, V_fixture 0.0: 20-80 % time 138ps typ, 146ps min, 133ps max; typ from 0.128 V to 0 V
[Pulldown]
|Voltage   I(typ)   I(min)   I(max)
-1.1V     -1.793mA   -1.671mA   -1.818mA
-998mV    -2.547mA   -2.269mA   -2.457mA
-862mV    -2.678mA   -2.659mA   -2.417mA
-488mV    -2.084mA   -2.079mA   -1.934mA
1.212V    5.262mA    5.292mA    4.958mA
1.79V     7.277mA    7.157mA    7.001mA
1.926V    7.641mA    6.913mA    7.467mA
1.994V    7.572mA    6.061mA    7.683mA
2.062V    6.74mA     4.852mA    7.735mA
2.096V    5.944mA    4.292mA    7.494mA
2.13V     5.072mA    3.814mA    6.855mA
2.2V      3.635mA    3.086mA    4.66mA
[Pullup]
|Voltage   I(typ)   I(min)   I(max)
-1.1V     709.3uA    760.2uA    557.1uA
-996mV    1.163mA    1.078mA    1.025mA
-894mV    1.523mA    1.472mA    1.204mA
-758mV    1.557mA    1.642mA    1.218mA
-486mV    1.368mA    1.374mA    1.168mA
-316mV    997.2uA    993.3uA    894.4uA
568mV     -1.684mA   -1.725mA   -1.482mA
1.52V     -3.531mA   -3.778mA   -2.901mA
1.928V    -3.392mA   -3.623mA   -2.673mA
2.064V    -3.122mA   -2.911mA   -2.51mA
2.132V    -2.646mA   -2.329mA   -2.358mA
2.2V      -1.968mA   -1.858mA   -1.925mA
[GND_clamp]
|Voltage   I(typ)   I(min)   I(max)
-1.1V     -68.65mA   -82.91mA   -64.16mA
-1.054V   -51.26mA   -62.87mA   -50.37mA
-1.008V   -39.63mA   -47.13mA   -42.26mA
-962mV    -32.34mA   -35.82mA   -36.73mA
-916mV    -27.28mA   -28.13mA   -32.02mA
-847mV    -21.22mA   -20.63mA   -25.4mA
-778mV    -15.81mA   -15.27mA   -19.09mA
-663mV    -7.926mA   -8.201mA   -9.607mA
-571mV    -3.246mA   -3.982mA   -3.828mA
-502mV    -1.097mA   -1.819mA   -1.164mA
-410mV    -96.97uA   -374.9uA   -57.53uA
1.1V      0A         0A         0A
[POWER_clamp]
|Voltage   I(typ)   I(min)   I(max)
-1.085V   71.41mA    95.35mA    58.18mA
-1.062V   59.23mA    82.55mA    46.99mA
-1.039V   48.36mA    70.56mA    37.71mA
-1.016V   38.97mA    59.53mA    30.53mA
-970mV    25.17mA    40.76mA    21.88mA
-924mV    17.37mA    26.93mA    17.87mA
-901mV    15.03mA    21.86mA    16.59mA
-855mV    12.01mA    14.79mA    14.5mA
-763mV    8.448mA    8.108mA    10.89mA
-533mV    2.369mA    2.267mA    3.272mA
-349mV    143.9uA    291.4uA    171.3uA
1.1V      0A         0A         0A
[Ramp]
| variable   typ   min   max
dV/dt_r   76.556m/0.170n   78.807m/0.180n   66.720m/0.162n
dV/dt_f   0.119/0.151n   0.116/0.170n   0.115/0.141n
R_load = 50.000
[Rising Waveform]
R_fixture= 50.000
V_fixture= 0.0
V_fixture_min= 0.0
V_fixture_max= 0.0
|time   V(typ)   V(min)   V(max)
0s        2.271uV    12.08uV    1.02uV
391ps     287.9uV    148.9uV    431.3uV
494ps     1.335mV    -26.04uV   53.03mV
574ps     46.2mV     -630.1uV   82.55mV
613ps     68.18mV    11.9mV     90.97mV
682ps     94.68mV    52.46mV    100.2mV
821ps     117.7mV    105.6mV    107.9mV
961ps     124.5mV    123.2mV    110.2mV
1.162ns   127mV      129.7mV    111mV
10ns      127.6mV    131.4mV    111.2mV
[Rising Waveform]
R_fixture= 50.000
V_fixture= 0.550
V_fixture_min= 0.534
V_fixture_max= 0.568
|time   V(typ)   V(min)   V(max)
0s        450.6mV    436.2mV    471.2mV
397ps     450.8mV    436.4mV    472.5mV
497ps     457.7mV    436.2mV    556.7mV
571ps     519.6mV    438.9mV    595.6mV
612ps     551.2mV    455.6mV    607.9mV
662ps     577.2mV    498.4mV    617.7mV
777ps     606.3mV    565.5mV    628.6mV
872ps     615.5mV    588mV      632mV
1.027ns   620.7mV    601mV      633.9mV
10ns      622.6mV    605.9mV    634.5mV
[Falling Waveform]
R_fixture= 50.000
V_fixture= 0.550
V_fixture_min= 0.534
V_fixture_max= 0.568
|time   V(typ)   V(min)   V(max)
0s        622.6mV    605.9mV    634.5mV
383ps     622.5mV    605.8mV    634.8mV
486ps     619.2mV    606.2mV    539mV
562ps     542.6mV    605.4mV    502.7mV
596ps     516.1mV    590.9mV    493.7mV
636ps     494.9mV    553.4mV    486.4mV
742ps     466.9mV    480.7mV    476.7mV
842ps     457.1mV    454.6mV    473.3mV
969ps     452.7mV    442.5mV    471.8mV
10ns      450.6mV    436.2mV    471.2mV
[Falling Waveform]
R_fixture= 50.000
V_fixture= 0.0
V_fixture_min= 0.0
V_fixture_max= 0.0
|time   V(typ)   V(min)   V(max)
0s        127.6mV    131.4mV    111.2mV
384ps     127.6mV    131.3mV    111.6mV
481ps     126.3mV    132mV      50.09mV
556ps     73.4mV     131.4mV    23.19mV
637ps     31.89mV    87.53mV    10.44mV
692ps     18.71mV    50.85mV    6.132mV
762ps     9.669mV    25.92mV    3.15mV
882ps     3.226mV    8.753mV    1.038mV
1.082ns   575.9uV    1.611mV    188.1uV
10ns      2.249uV    12.06uV    1.003uV
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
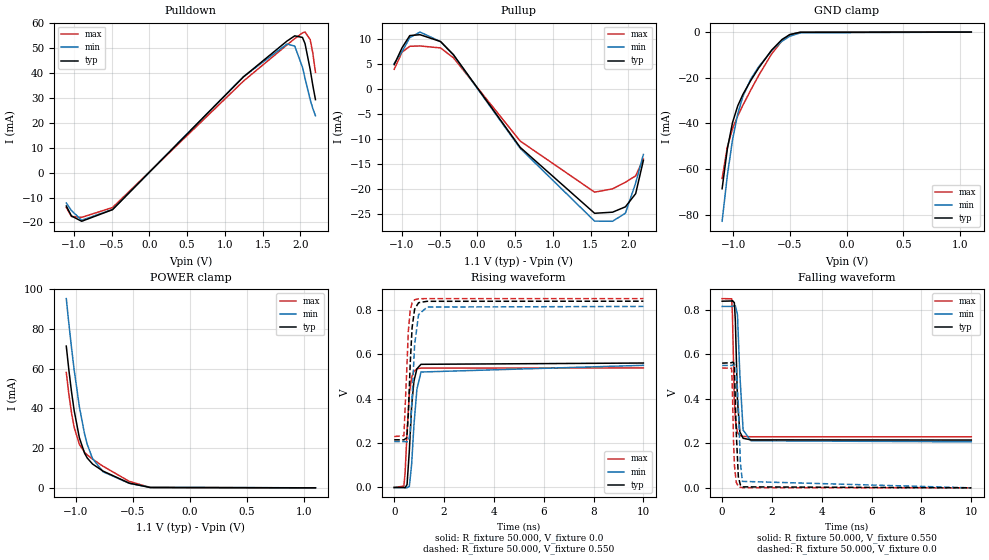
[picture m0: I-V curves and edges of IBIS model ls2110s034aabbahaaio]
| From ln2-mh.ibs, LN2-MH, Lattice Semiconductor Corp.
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|   Model ls2110s034aabbahaaio
[Model] ls2110s034aabbahaaio
| Clamp models do not include dynamic input termination. Please refer to
| the ls2110axxxaabbahaain model for input termination.
Model_type I/O
Polarity   Non-Inverting
Enable   Active-Low
Vinl =  0.200V
Vinh =  0.300V
Vmeas =  0.550V
Cref =  20.000pF
Rref =  50.000
Vref =  0.600V
C_comp   2.000pF   1.500pF   2.500pF
[Temperature Range]   25.000   0.125k   -40.000
[Voltage Range]   1.100V   1.070V   1.130V
[C Comp Corner]
C_comp   2.000pF   1.500pF   2.500pF
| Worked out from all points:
|   slope of the pulldown table from 0 to 0.165 V, typ, clamps not added: 31.9 ohm
|   slope of the pullup table from 0 to 0.165 V, typ, clamps not added: 45.3 ohm
|   GND clamp passes 1 mA (typ) near -0.50 V on its own axis
|   POWER clamp passes 1 mA (typ) near -0.45 V on its own axis
|   rising waveform, R_fixture 50.000, V_fixture 0.0: 20-80 % time 175ps typ, 206ps min, 157ps max; typ from 0 V to 0.56 V
|   rising waveform, R_fixture 50.000, V_fixture 0.550: 20-80 % time 145ps typ, 169ps min, 129ps max; typ from 0.214 V to 0.837 V
|   falling waveform, R_fixture 50.000, V_fixture 0.550: 20-80 % time 94.3ps typ, 123ps min, 80.6ps max; typ from 0.837 V to 0.214 V
|   falling waveform, R_fixture 50.000, V_fixture 0.0: 20-80 % time 85.5ps typ, 106ps min, 76.1ps max; typ from 0.56 V to 0 V
[Pulldown]
|Voltage   I(typ)   I(min)   I(max)
-1.1V     -13.39mA   -12.19mA   -13.95mA
-1.032V   -17.38mA   -15.19mA   -17.59mA
-896mV    -19.51mA   -19.08mA   -17.94mA
-488mV    -14.86mA   -14.78mA   -14.01mA
1.246V    38.35mA    38.42mA    36.65mA
1.824V    52.74mA    51.53mA    51.2mA
1.926V    54.81mA    50.69mA    53.7mA
2.028V    54.17mA    42.2mA     55.99mA
2.062V    51.67mA    37.77mA    56.33mA
2.13V     41.38mA    29.25mA    53.34mA
2.164V    35.13mA    25.8mA     48.11mA
2.2V      29.25mA    22.8mA     40.19mA
[Pullup]
|Voltage   I(typ)   I(min)   I(max)
-1.1V     4.877mA    5.08mA     3.939mA
-996mV    8.246mA    7.456mA    7.374mA
-894mV    10.69mA    10.28mA    8.55mA
-758mV    10.87mA    11.4mA     8.618mA
-486mV    9.499mA    9.475mA    8.22mA
-316mV    6.88mA     6.811mA    6.248mA
568mV     -11.67mA   -11.87mA   -10.41mA
1.554V    -24.87mA   -26.44mA   -20.64mA
1.792V    -24.65mA   -26.47mA   -19.98mA
1.962V    -23.58mA   -24.85mA   -18.66mA
2.098V    -20.94mA   -18.81mA   -17.38mA
2.2V      -14.29mA   -13.11mA   -14.03mA
[GND_clamp]
|Voltage   I(typ)   I(min)   I(max)
-1.1V     -68.65mA   -82.91mA   -64.16mA
-1.054V   -51.26mA   -62.87mA   -50.37mA
-1.008V   -39.63mA   -47.13mA   -42.26mA
-962mV    -32.34mA   -35.82mA   -36.73mA
-916mV    -27.28mA   -28.13mA   -32.02mA
-847mV    -21.22mA   -20.63mA   -25.4mA
-778mV    -15.81mA   -15.27mA   -19.09mA
-663mV    -7.926mA   -8.201mA   -9.607mA
-571mV    -3.246mA   -3.982mA   -3.828mA
-502mV    -1.097mA   -1.819mA   -1.164mA
-410mV    -96.97uA   -374.9uA   -57.53uA
1.1V      0A         0A         0A
[POWER_clamp]
|Voltage   I(typ)   I(min)   I(max)
-1.085V   71.41mA    95.35mA    58.18mA
-1.062V   59.23mA    82.55mA    46.99mA
-1.039V   48.36mA    70.56mA    37.71mA
-1.016V   38.97mA    59.53mA    30.53mA
-970mV    25.17mA    40.76mA    21.88mA
-924mV    17.37mA    26.93mA    17.87mA
-901mV    15.03mA    21.86mA    16.59mA
-855mV    12.01mA    14.79mA    14.5mA
-763mV    8.448mA    8.108mA    10.89mA
-533mV    2.369mA    2.267mA    3.272mA
-349mV    143.9uA    291.4uA    171.3uA
1.1V      0A         0A         0A
[Ramp]
| variable   typ   min   max
dV/dt_r   0.336/0.175n   0.330/0.205n   0.323/0.157n
dV/dt_f   0.402/0.104n   0.393/0.141n   0.404/85.890p
R_load = 50.000
[Rising Waveform]
R_fixture= 50.000
V_fixture= 0.0
V_fixture_min= 0.0
V_fixture_max= 0.0
|time   V(typ)   V(min)   V(max)
0s        961.4nV    5.179uV    441nV
388ps     -72.8uV    54.61uV    6.148mV
438ps     -1.537mV   66.76uV    66.68mV
516ps     13.2mV     -1.367mV   249.3mV
608ps     165.4mV    5.356mV    422.4mV
701ps     367.6mV    105.7mV    495.7mV
791ps     477.5mV    278.7mV    522mV
911ps     533.6mV    441.2mV    533.3mV
1.075ns   553.7mV    519.1mV    536.7mV
10ns      559.5mV    549.2mV    537.6mV
[Rising Waveform]
R_fixture= 50.000
V_fixture= 0.550
V_fixture_min= 0.534
V_fixture_max= 0.568
|time   V(typ)   V(min)   V(max)
0s        214.4mV    206.4mV    229.1mV
390ps     214.3mV    206.4mV    232.8mV
509ps     223.8mV    205.6mV    541.9mV
567ps     332.1mV    206mV      702.4mV
644ps     560mV      246.9mV    797.7mV
718ps     718.2mV    405mV      830mV
819ps     801.3mV    640.9mV    843.8mV
979ps     830.8mV    777.4mV    848.3mV
1.319ns   837mV      811.1mV    849.1mV
10ns      837.4mV    813.9mV    849.1mV
[Falling Waveform]
R_fixture= 50.000
V_fixture= 0.550
V_fixture_min= 0.534
V_fixture_max= 0.568
|time   V(typ)   V(min)   V(max)
0s        837.4mV    813.9mV    849.1mV
383ps     838.5mV    814mV      848.2mV
415ps     840.2mV    814.4mV    774.7mV
491ps     830.7mV    816.8mV    394.7mV
532ps     748.3mV    817mV      305.1mV
616ps     390.3mV    777.2mV    248mV
712ps     251.4mV    506.7mV    234.3mV
843ps     222.3mV    259.3mV    230.5mV
1.153ns   215.3mV    211.2mV    229.2mV
10ns      214.4mV    206.4mV    229.1mV
[Falling Waveform]
R_fixture= 50.000
V_fixture= 0.0
V_fixture_min= 0.0
V_fixture_max= 0.0
|time   V(typ)   V(min)   V(max)
0s        559.5mV    549.2mV    537.5mV
377ps     561.4mV    549.3mV    536.6mV
404ps     563.4mV    549.9mV    477.8mV
458ps     563.2mV    552.2mV    211.2mV
493ps     534.6mV    554.1mV    102.9mV
567ps     250.3mV    542.8mV    24.89mV
651ps     50.13mV    370.5mV    6.386mV
733ps     12.76mV    113.9mV    2.088mV
813ps     4.367mV    28.94mV    849.2uV
10ns      946nV      5.157uV    427.9nV
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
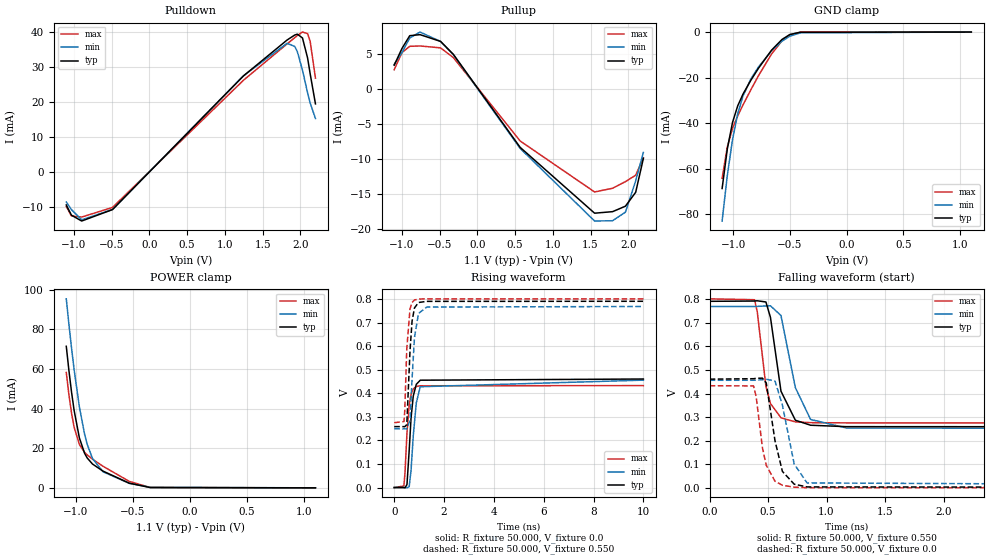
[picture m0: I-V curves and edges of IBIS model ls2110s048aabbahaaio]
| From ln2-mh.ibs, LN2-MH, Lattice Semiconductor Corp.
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|   Model ls2110s048aabbahaaio
[Model] ls2110s048aabbahaaio
| Clamp models do not include dynamic input termination. Please refer to
| the ls2110axxxaabbahaain model for input termination.
Model_type I/O
Polarity   Non-Inverting
Enable   Active-Low
Vinl =  0.200V
Vinh =  0.300V
Vmeas =  0.550V
Cref =  20.000pF
Rref =  50.000
Vref =  0.600V
C_comp   2.000pF   1.500pF   2.500pF
[Temperature Range]   25.000   0.125k   -40.000
[Voltage Range]   1.100V   1.070V   1.130V
[C Comp Corner]
C_comp   2.000pF   1.500pF   2.500pF
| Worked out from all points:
|   slope of the pulldown table from 0 to 0.165 V, typ, clamps not added: 44.4 ohm
|   slope of the pullup table from 0 to 0.165 V, typ, clamps not added: 63.1 ohm
|   GND clamp passes 1 mA (typ) near -0.50 V on its own axis
|   POWER clamp passes 1 mA (typ) near -0.45 V on its own axis
|   rising waveform, R_fixture 50.000, V_fixture 0.0: 20-80 % time 170ps typ, 206ps min, 151ps max; typ from 0 V to 0.461 V
|   rising waveform, R_fixture 50.000, V_fixture 0.550: 20-80 % time 139ps typ, 168ps min, 123ps max; typ from 0.259 V to 0.791 V
|   falling waveform, R_fixture 50.000, V_fixture 0.550: 20-80 % time 103ps typ, 136ps min, 86ps max; typ from 0.791 V to 0.259 V
|   falling waveform, R_fixture 50.000, V_fixture 0.0: 20-80 % time 90.9ps typ, 113ps min, 81.6ps max; typ from 0.461 V to 0 V
[Pulldown]
|Voltage   I(typ)   I(min)   I(max)
-1.1V     -9.331mA   -8.492mA   -9.729mA
-1.032V   -12.24mA   -10.65mA   -12.45mA
-896mV    -13.91mA   -13.57mA   -12.78mA
-488mV    -10.65mA   -10.6mA    -10.03mA
1.246V    27.54mA    27.59mA    26.3mA
1.824V    37.8mA     36.87mA    36.7mA
1.926V    39.24mA    35.96mA    38.49mA
1.96V     39.48mA    34.49mA    39.08mA
2.028V    38.4mA     29.21mA    40.09mA
2.096V    32.66mA    22.68mA    39.63mA
2.13V     28.15mA    19.83mA    37.42mA
2.2V      19.56mA    15.36mA    26.91mA
[Pullup]
|Voltage   I(typ)   I(min)   I(max)
-1.1V     3.391mA    3.517mA    2.749mA
-996mV    5.814mA    5.23mA     5.224mA
-894mV    7.622mA    7.298mA    6.097mA
-758mV    7.769mA    8.144mA    6.15mA
-486mV    6.803mA    6.791mA    5.876mA
-316mV    4.941mA    4.892mA    4.481mA
568mV     -8.372mA   -8.524mA   -7.458mA
1.554V    -17.8mA    -18.92mA   -14.76mA
1.792V    -17.58mA   -18.88mA   -14.23mA
1.962V    -16.8mA    -17.66mA   -13.28mA
2.098V    -14.81mA   -13.18mA   -12.36mA
2.2V      -9.957mA   -9.113mA   -9.868mA
[GND_clamp]
|Voltage   I(typ)   I(min)   I(max)
-1.1V     -68.65mA   -82.91mA   -64.16mA
-1.054V   -51.26mA   -62.87mA   -50.37mA
-1.008V   -39.63mA   -47.13mA   -42.26mA
-962mV    -32.34mA   -35.82mA   -36.73mA
-916mV    -27.28mA   -28.13mA   -32.02mA
-847mV    -21.22mA   -20.63mA   -25.4mA
-778mV    -15.81mA   -15.27mA   -19.09mA
-663mV    -7.926mA   -8.201mA   -9.607mA
-571mV    -3.246mA   -3.982mA   -3.828mA
-502mV    -1.097mA   -1.819mA   -1.164mA
-410mV    -96.97uA   -374.9uA   -57.53uA
1.1V      0A         0A         0A
[POWER_clamp]
|Voltage   I(typ)   I(min)   I(max)
-1.085V   71.41mA    95.35mA    58.18mA
-1.062V   59.23mA    82.55mA    46.99mA
-1.039V   48.36mA    70.56mA    37.71mA
-1.016V   38.97mA    59.53mA    30.53mA
-970mV    25.17mA    40.76mA    21.88mA
-924mV    17.37mA    26.93mA    17.87mA
-901mV    15.03mA    21.86mA    16.59mA
-855mV    12.01mA    14.79mA    14.5mA
-763mV    8.448mA    8.108mA    10.89mA
-533mV    2.369mA    2.267mA    3.272mA
-349mV    143.9uA    291.4uA    171.3uA
1.1V      0A         0A         0A
[Ramp]
| variable   typ   min   max
dV/dt_r   0.277/0.170n   0.274/0.206n   0.260/0.151n
dV/dt_f   0.349/0.116n   0.341/0.161n   0.349/91.395p
R_load = 50.000
[Rising Waveform]
R_fixture= 50.000
V_fixture= 0.0
V_fixture_min= 0.0
V_fixture_max= 0.0
|time   V(typ)   V(min)   V(max)
0s        1.208uV    6.471uV    552nV
388ps     -61.08uV   63.62uV    6.599mV
435ps     -1.274mV   79.36uV    65.14mV
513ps     12.91mV    -1.178mV   233mV
601ps     157.2mV    3.642mV    350.1mV
677ps     296.7mV    73.92mV    396.1mV
766ps     389.2mV    221mV      418.8mV
887ps     438.6mV    359.9mV    429.2mV
1.047ns   456.1mV    428.3mV    432.4mV
10ns      461.1mV    456.3mV    433.1mV
[Rising Waveform]
R_fixture= 50.000
V_fixture= 0.550
V_fixture_min= 0.534
V_fixture_max= 0.568
|time   V(typ)   V(min)   V(max)
0s        258.9mV    249.5mV    275.5mV
392ps     258.8mV    249.5mV    280.3mV
422ps     258.2mV    249.6mV    322.1mV
505ps     267.4mV    248.8mV    590mV
635ps     582mV      285.4mV    759.3mV
717ps     707.1mV    461.8mV    786.3mV
814ps     763.1mV    637.9mV    796.9mV
974ps     786.1mV    739.4mV    800.8mV
1.304ns   791mV      766.8mV    801.6mV
10ns      791.3mV    769.2mV    801.6mV
[Falling Waveform]
R_fixture= 50.000
V_fixture= 0.550
V_fixture_min= 0.534
V_fixture_max= 0.568
|time   V(typ)   V(min)   V(max)
0s        791.2mV    769.2mV    801.6mV
384ps     792.4mV    769.3mV    798mV
407ps     793.5mV    769.6mV    747.3mV
481ps     788.4mV    771.7mV    430.9mV
520ps     722.9mV    772.3mV    357.7mV
610ps     409.8mV    730.9mV    296.9mV
733ps     286.8mV    424.9mV    279.8mV
863ps     265.6mV    290.2mV    276.5mV
1.172ns   259.5mV    253.6mV    275.6mV
10ns      258.9mV    249.5mV    275.5mV
[Falling Waveform]
R_fixture= 50.000
V_fixture= 0.0
V_fixture_min= 0.0
V_fixture_max= 0.0
|time   V(typ)   V(min)   V(max)
0s        461mV      456.3mV    433.1mV
375ps     462.9mV    456.4mV    432.4mV
398ps     464.5mV    456.8mV    386mV
451ps     465.4mV    458.9mV    170.9mV
484ps     445.1mV    460.8mV    95.56mV
559ps     199.3mV    453mV      28.1mV
622ps     69.8mV     351.3mV    11.03mV
723ps     15.52mV    101mV      2.824mV
833ps     3.916mV    20.88mV    774.5uV
10ns      1.191uV    6.451uV    537.3nV
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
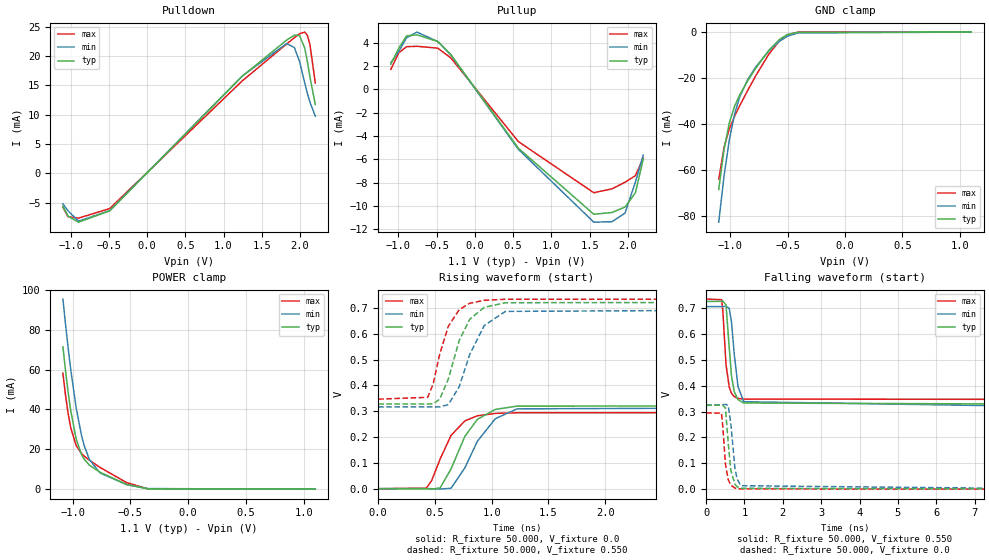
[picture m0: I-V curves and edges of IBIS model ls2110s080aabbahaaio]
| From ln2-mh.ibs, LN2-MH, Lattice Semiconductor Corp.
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|   Model ls2110s080aabbahaaio
[Model] ls2110s080aabbahaaio
| Clamp models do not include dynamic input termination. Please refer to
| the ls2110axxxaabbahaain model for input termination.
Model_type I/O
Polarity   Non-Inverting
Enable   Active-Low
Vinl =  0.200V
Vinh =  0.300V
Vmeas =  0.550V
Cref =  20.000pF
Rref =  50.000
Vref =  0.600V
C_comp   2.000pF   1.500pF   2.500pF
[Temperature Range]   25.000   0.125k   -40.000
[Voltage Range]   1.100V   1.070V   1.130V
[C Comp Corner]
C_comp   2.000pF   1.500pF   2.500pF
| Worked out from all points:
|   slope of the pulldown table from 0 to 0.165 V, typ, clamps not added: 73.8 ohm
|   slope of the pullup table from 0 to 0.165 V, typ, clamps not added: 104 ohm
|   GND clamp passes 1 mA (typ) near -0.50 V on its own axis
|   POWER clamp passes 1 mA (typ) near -0.45 V on its own axis
|   rising waveform, R_fixture 50.000, V_fixture 0.0: 20-80 % time 221ps typ, 256ps min, 193ps max; typ from 0 V to 0.324 V
|   rising waveform, R_fixture 50.000, V_fixture 0.550: 20-80 % time 183ps typ, 213ps min, 155ps max; typ from 0.328 V to 0.725 V
|   falling waveform, R_fixture 50.000, V_fixture 0.550: 20-80 % time 129ps typ, 160ps min, 113ps max; typ from 0.725 V to 0.328 V
|   falling waveform, R_fixture 50.000, V_fixture 0.0: 20-80 % time 113ps typ, 128ps min, 104ps max; typ from 0.324 V to 0 V
[Pulldown]
|Voltage   I(typ)   I(min)   I(max)
-1.1V     -5.63mA    -5.217mA   -5.79mA
-1.032V   -7.317mA   -6.439mA   -7.425mA
-896mV    -8.348mA   -8.148mA   -7.654mA
-488mV    -6.408mA   -6.379mA   -6.018mA
1.246V    16.59mA    16.63mA    15.8mA
1.824V    22.74mA    22.16mA    22.07mA
1.926V    23.59mA    21.49mA    23.15mA
1.994V    23.53mA    19.11mA    23.83mA
2.062V    21.38mA    15.45mA    24.12mA
2.096V    19.11mA    13.68mA    23.59mA
2.13V     16.44mA    12.14mA    21.98mA
2.2V      11.76mA    9.772mA    15.43mA
[Pullup]
|Voltage   I(typ)   I(min)   I(max)
-1.1V     2.15mA     2.287mA    1.709mA
-996mV    3.524mA    3.244mA    3.134mA
-894mV    4.58mA     4.417mA    3.654mA
-758mV    4.67mA     4.905mA    3.687mA
-486mV    4.097mA    4.096mA    3.528mA
-316mV    2.982mA    2.956mA    2.698mA
568mV     -5.048mA   -5.147mA   -4.484mA
1.554V    -10.71mA   -11.39mA   -8.866mA
1.792V    -10.56mA   -11.35mA   -8.53mA
1.962V    -10.09mA   -10.61mA   -7.964mA
2.098V    -8.866mA   -7.952mA   -7.404mA
2.2V      -6.01mA    -5.644mA   -5.887mA
[GND_clamp]
|Voltage   I(typ)   I(min)   I(max)
-1.1V     -68.65mA   -82.91mA   -64.16mA
-1.054V   -51.26mA   -62.87mA   -50.37mA
-1.008V   -39.63mA   -47.13mA   -42.26mA
-962mV    -32.34mA   -35.82mA   -36.73mA
-916mV    -27.28mA   -28.13mA   -32.02mA
-847mV    -21.22mA   -20.63mA   -25.4mA
-778mV    -15.81mA   -15.27mA   -19.09mA
-663mV    -7.926mA   -8.201mA   -9.607mA
-571mV    -3.246mA   -3.982mA   -3.828mA
-502mV    -1.097mA   -1.819mA   -1.164mA
-410mV    -96.97uA   -374.9uA   -57.53uA
1.1V      0A         0A         0A
[POWER_clamp]
|Voltage   I(typ)   I(min)   I(max)
-1.085V   71.41mA    95.35mA    58.18mA
-1.062V   59.23mA    82.55mA    46.99mA
-1.039V   48.36mA    70.56mA    37.71mA
-1.016V   38.97mA    59.53mA    30.53mA
-970mV    25.17mA    40.76mA    21.88mA
-924mV    17.37mA    26.93mA    17.87mA
-901mV    15.03mA    21.86mA    16.59mA
-855mV    12.01mA    14.79mA    14.5mA
-763mV    8.448mA    8.108mA    10.89mA
-533mV    2.369mA    2.267mA    3.272mA
-349mV    143.9uA    291.4uA    171.3uA
1.1V      0A         0A         0A
[Ramp]
| variable   typ   min   max
dV/dt_r   0.194/0.221n   0.195/0.256n   0.177/0.193n
dV/dt_f   0.266/0.144n   0.261/0.186n   0.264/0.124n
R_load = 50.000
[Rising Waveform]
R_fixture= 50.000
V_fixture= 0.0
V_fixture_min= 0.0
V_fixture_max= 0.0
|time   V(typ)   V(min)   V(max)
0s        1.59uV     8.481uV    722.6nV
424ps     -256.2uV   202.6uV    2.138mV
472ps     -1.849mV   81.22uV    32.26mV
546ps     3.132mV    -1.366mV   115.3mV
642ps     76.64mV    1.786mV    206.4mV
763ps     202.3mV    80.36mV    262.5mV
874ps     268.6mV    183.8mV    282.4mV
1.032ns   307mV      271.1mV    291.6mV
1.223ns   319.7mV    309.1mV    294.1mV
10ns      323.6mV    325mV      294.6mV
[Rising Waveform]
R_fixture= 50.000
V_fixture= 0.550
V_fixture_min= 0.534
V_fixture_max= 0.568
|time   V(typ)   V(min)   V(max)
0s        328mV      316.5mV    346.8mV
436ps     327.7mV    316.7mV    353.8mV
484ps     328.9mV    316.4mV    405.3mV
542ps     346.6mV    316.5mV    520.8mV
618ps     424.7mV    326mV      629mV
714ps     574.5mV    394.8mV    693.4mV
806ps     655.9mV    520mV      718.1mV
935ps     702.6mV    632.2mV    729.8mV
1.121ns   720.3mV    686.7mV    733.6mV
10ns      724.9mV    705.1mV    734.4mV
[Falling Waveform]
R_fixture= 50.000
V_fixture= 0.550
V_fixture_min= 0.534
V_fixture_max= 0.568
|time   V(typ)   V(min)   V(max)
0s        724.9mV    705.1mV    734.4mV
406ps     725.7mV    705.2mV    732mV
437ps     726.6mV    705.4mV    688.1mV
519ps     712.1mV    706.9mV    480.8mV
603ps     546.3mV    698.3mV    393.9mV
662ps     438.2mV    645.8mV    370.4mV
732ps     377.6mV    524.3mV    357.8mV
832ps     345.7mV    396.1mV    350.8mV
982ps     332.8mV    337.8mV    348mV
10ns      328mV      316.5mV    346.8mV
[Falling Waveform]
R_fixture= 50.000
V_fixture= 0.0
V_fixture_min= 0.0
V_fixture_max= 0.0
|time   V(typ)   V(min)   V(max)
0s        323.6mV    325mV      294.6mV
400ps     324.9mV    325.1mV    293.7mV
423ps     325.8mV    325.4mV    265.6mV
504ps     314mV      327.8mV    97.14mV
577ps     176.4mV    323.7mV    36.31mV
645ps     71.63mV    253.1mV    15.34mV
753ps     18.46mV    78.68mV    4.279mV
812ps     9.336mV    38.36mV    2.25mV
905ps     3.467mV    13.4mV     899.6uV
10ns      1.569uV    8.458uV    705.7nV
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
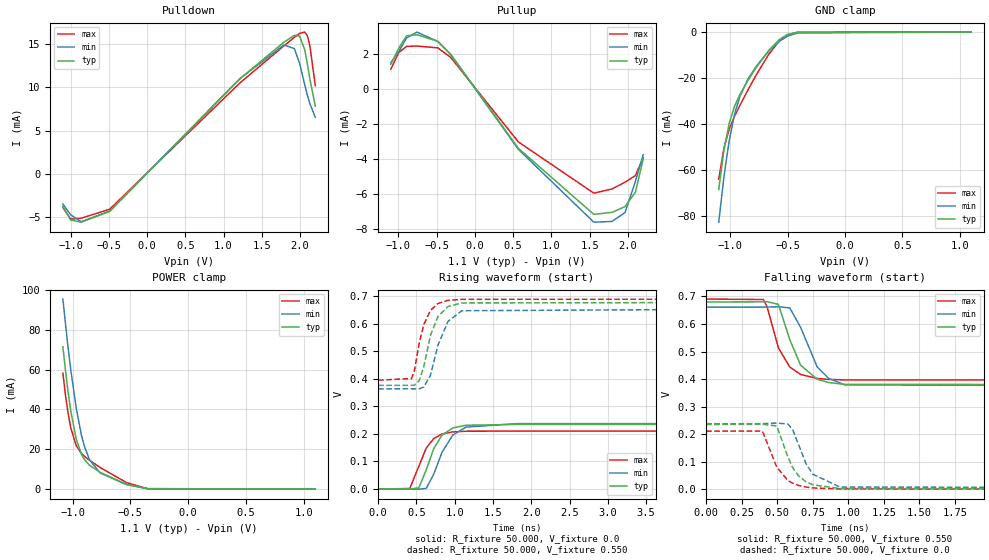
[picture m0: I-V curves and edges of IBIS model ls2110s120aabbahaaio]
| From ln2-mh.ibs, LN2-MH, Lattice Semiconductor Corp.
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|   Model ls2110s120aabbahaaio
[Model] ls2110s120aabbahaaio
| Clamp models do not include dynamic input termination. Please refer to
| the ls2110axxxaabbahaain model for input termination.
Model_type I/O
Polarity   Non-Inverting
Enable   Active-Low
Vinl =  0.200V
Vinh =  0.300V
Vmeas =  0.550V
Cref =  20.000pF
Rref =  50.000
Vref =  0.600V
C_comp   2.000pF   1.500pF   2.500pF
[Temperature Range]   25.000   0.125k   -40.000
[Voltage Range]   1.100V   1.070V   1.130V
[C Comp Corner]
C_comp   2.000pF   1.500pF   2.500pF
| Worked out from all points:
|   slope of the pulldown table from 0 to 0.165 V, typ, clamps not added: 108 ohm
|   slope of the pullup table from 0 to 0.165 V, typ, clamps not added: 156 ohm
|   GND clamp passes 1 mA (typ) near -0.50 V on its own axis
|   POWER clamp passes 1 mA (typ) near -0.45 V on its own axis
|   rising waveform, R_fixture 50.000, V_fixture 0.0: 20-80 % time 209ps typ, 239ps min, 191ps max; typ from 0 V to 0.235 V
|   rising waveform, R_fixture 50.000, V_fixture 0.550: 20-80 % time 174ps typ, 201ps min, 155ps max; typ from 0.377 V to 0.68 V
|   falling waveform, R_fixture 50.000, V_fixture 0.550: 20-80 % time 135ps typ, 158ps min, 125ps max; typ from 0.68 V to 0.377 V
|   falling waveform, R_fixture 50.000, V_fixture 0.0: 20-80 % time 122ps typ, 132ps min, 117ps max; typ from 0.235 V to 0 V
[Pulldown]
|Voltage   I(typ)   I(min)   I(max)
-1.1V     -3.788mA   -3.514mA   -3.915mA
-998mV    -5.355mA   -4.765mA   -5.25mA
-862mV    -5.61mA    -5.559mA   -5.155mA
-488mV    -4.353mA   -4.328mA   -4.108mA
1.212V    10.98mA    11mA       10.5mA
1.79V     15.24mA    14.92mA    14.82mA
1.926V    16.03mA    14.5mA     15.8mA
1.994V    15.95mA    12.81mA    16.26mA
2.062V    14.36mA    10.31mA    16.41mA
2.096V    12.76mA    9.126mA    15.99mA
2.13V     10.93mA    8.106mA    14.77mA
2.2V      7.825mA    6.542mA    10.21mA
[Pullup]
|Voltage   I(typ)   I(min)   I(max)
-1.1V     1.431mA    1.519mA    1.144mA
-996mV    2.344mA    2.153mA    2.098mA
-894mV    3.054mA    2.935mA    2.449mA
-758mV    3.115mA    3.266mA    2.469mA
-486mV    2.737mA    2.731mA    2.364mA
-316mV    1.997mA    1.974mA    1.813mA
568mV     -3.38mA    -3.44mA    -3.014mA
1.554V    -7.157mA   -7.603mA   -5.943mA
1.792V    -7.039mA   -7.561mA   -5.703mA
1.962V    -6.716mA   -7.052mA   -5.316mA
2.098V    -5.883mA   -5.265mA   -4.937mA
2.2V      -3.975mA   -3.74mA    -3.911mA
[GND_clamp]
|Voltage   I(typ)   I(min)   I(max)
-1.1V     -68.65mA   -82.91mA   -64.16mA
-1.054V   -51.26mA   -62.87mA   -50.37mA
-1.008V   -39.63mA   -47.13mA   -42.26mA
-962mV    -32.34mA   -35.82mA   -36.73mA
-916mV    -27.28mA   -28.13mA   -32.02mA
-847mV    -21.22mA   -20.63mA   -25.4mA
-778mV    -15.81mA   -15.27mA   -19.09mA
-663mV    -7.926mA   -8.201mA   -9.607mA
-571mV    -3.246mA   -3.982mA   -3.828mA
-502mV    -1.097mA   -1.819mA   -1.164mA
-410mV    -96.97uA   -374.9uA   -57.53uA
1.1V      0A         0A         0A
[POWER_clamp]
|Voltage   I(typ)   I(min)   I(max)
-1.085V   71.41mA    95.35mA    58.18mA
-1.062V   59.23mA    82.55mA    46.99mA
-1.039V   48.36mA    70.56mA    37.71mA
-1.016V   38.97mA    59.53mA    30.53mA
-970mV    25.17mA    40.76mA    21.88mA
-924mV    17.37mA    26.93mA    17.87mA
-901mV    15.03mA    21.86mA    16.59mA
-855mV    12.01mA    14.79mA    14.5mA
-763mV    8.448mA    8.108mA    10.89mA
-533mV    2.369mA    2.267mA    3.272mA
-349mV    143.9uA    291.4uA    171.3uA
1.1V      0A         0A         0A
[Ramp]
| variable   typ   min   max
dV/dt_r   0.141/0.209n   0.143/0.239n   0.126/0.191n
dV/dt_f   0.207/0.151n   0.203/0.184n   0.205/0.135n
R_load = 50.000
[Rising Waveform]
R_fixture= 50.000
V_fixture= 0.0
V_fixture_min= 0.0
V_fixture_max= 0.0
|time   V(typ)   V(min)   V(max)
0s        1.863uV    9.921uV    840.8nV
413ps     17.71uV    181.4uV    1.699mV
530ps     3.835mV    -627.9uV   82.33mV
627ps     69.22mV    2.026mV    148.6mV
724ps     146.1mV    52.87mV    183mV
833ps     195.6mV    133.2mV    199.9mV
974ps     222.1mV    195.8mV    207.6mV
1.145ns   231.7mV    224.9mV    210mV
1.813ns   234.9mV    237.7mV    210.7mV
10ns      234.9mV    237.8mV    210.7mV
[Rising Waveform]
R_fixture= 50.000
V_fixture= 0.550
V_fixture_min= 0.534
V_fixture_max= 0.568
|time   V(typ)   V(min)   V(max)
0s        376.7mV    364.2mV    395.6mV
436ps     376.6mV    364.4mV    401.7mV
474ps     377.6mV    364.2mV    431.5mV
538ps     394.9mV    364.3mV    533.8mV
597ps     446.7mV    371.3mV    598.7mV
683ps     559mV      413.7mV    649.6mV
781ps     627.6mV    523.2mV    674.5mV
911ps     663.3mV    609mV      685.9mV
1.091ns   676.6mV    648.2mV    689.7mV
10ns      680mV      661.3mV    690.6mV
[Falling Waveform]
R_fixture= 50.000
V_fixture= 0.550
V_fixture_min= 0.534
V_fixture_max= 0.568
|time   V(typ)   V(min)   V(max)
0s        680mV      661.3mV    690.6mV
403ps     680.6mV    661.4mV    689mV
429ps     681.2mV    661.5mV    662.9mV
509ps     671.3mV    662.8mV    513.1mV
589ps     542.9mV    658.4mV    443.5mV
666ps     449.7mV    587mV      416.6mV
782ps     399.3mV    443.7mV    402.1mV
862ps     387.4mV    402.6mV    398.7mV
977ps     380.7mV    379mV      396.8mV
10ns      376.7mV    364.2mV    395.6mV
[Falling Waveform]
R_fixture= 50.000
V_fixture= 0.0
V_fixture_min= 0.0
V_fixture_max= 0.0
|time   V(typ)   V(min)   V(max)
0s        234.9mV    237.8mV    210.7mV
396ps     235.9mV    237.9mV    210.8mV
497ps     229.5mV    240.1mV    80.34mV
576ps     116.8mV    236.7mV    31.39mV
609ps     78.64mV    216.6mV    21.5mV
648ps     49.78mV    165.1mV    13.88mV
703ps     26.83mV    92.69mV    7.59mV
751ps     15.93mV    54.3mV     4.544mV
942ps     2.343mV    7.688mV    700uV
10ns      1.841uV    9.901uV    822.7nV
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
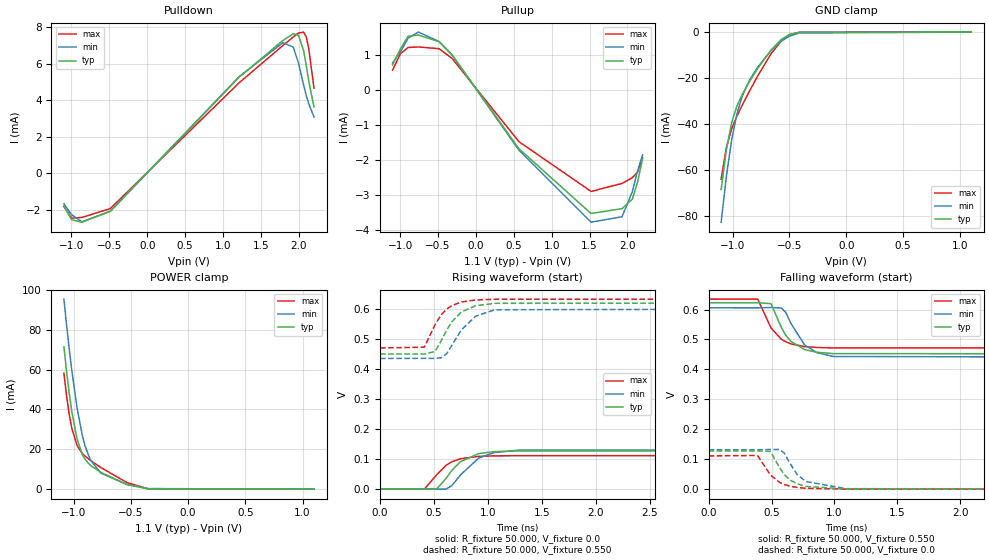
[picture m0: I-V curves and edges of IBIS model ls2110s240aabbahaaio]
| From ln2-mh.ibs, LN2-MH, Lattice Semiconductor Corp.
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|   Model ls2110s240aabbahaaio
[Model] ls2110s240aabbahaaio
| Clamp models do not include dynamic input termination. Please refer to
| the ls2110axxxaabbahaain model for input termination.
Model_type I/O
Polarity   Non-Inverting
Enable   Active-Low
Vinl =  0.200V
Vinh =  0.300V
Vmeas =  0.550V
Cref =  20.000pF
Rref =  50.000
Vref =  0.600V
C_comp   2.000pF   1.500pF   2.500pF
[Temperature Range]   25.000   0.125k   -40.000
[Voltage Range]   1.100V   1.070V   1.130V
[C Comp Corner]
C_comp   2.000pF   1.500pF   2.500pF
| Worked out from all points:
|   slope of the pulldown table from 0 to 0.165 V, typ, clamps not added: 226 ohm
|   slope of the pullup table from 0 to 0.165 V, typ, clamps not added: 313 ohm
|   GND clamp passes 1 mA (typ) near -0.50 V on its own axis
|   POWER clamp passes 1 mA (typ) near -0.45 V on its own axis
|   rising waveform, R_fixture 50.000, V_fixture 0.0: 20-80 % time 199ps typ, 223ps min, 179ps max; typ from 0 V to 0.128 V
|   rising waveform, R_fixture 50.000, V_fixture 0.550: 20-80 % time 189ps typ, 213ps min, 167ps max; typ from 0.451 V to 0.623 V
|   falling waveform, R_fixture 50.000, V_fixture 0.550: 20-80 % time 145ps typ, 162ps min, 137ps max; typ from 0.623 V to 0.451 V
|   falling waveform, R_fixture 50.000, V_fixture 0.0: 20-80 % time 138ps typ, 146ps min, 133ps max; typ from 0.128 V to 0 V
[Pulldown]
|Voltage   I(typ)   I(min)   I(max)
-1.1V     -1.793mA   -1.671mA   -1.818mA
-998mV    -2.547mA   -2.269mA   -2.457mA
-862mV    -2.678mA   -2.659mA   -2.417mA
-488mV    -2.084mA   -2.079mA   -1.934mA
1.212V    5.262mA    5.292mA    4.958mA
1.79V     7.277mA    7.157mA    7.001mA
1.926V    7.641mA    6.913mA    7.467mA
1.994V    7.572mA    6.061mA    7.683mA
2.062V    6.74mA     4.852mA    7.735mA
2.096V    5.944mA    4.292mA    7.494mA
2.13V     5.072mA    3.814mA    6.855mA
2.2V      3.635mA    3.086mA    4.66mA
[Pullup]
|Voltage   I(typ)   I(min)   I(max)
-1.1V     709.3uA    760.2uA    557.1uA
-996mV    1.163mA    1.077mA    1.025mA
-894mV    1.523mA    1.472mA    1.204mA
-758mV    1.557mA    1.642mA    1.218mA
-486mV    1.368mA    1.374mA    1.168mA
-316mV    997.2uA    993.3uA    894.4uA
568mV     -1.684mA   -1.725mA   -1.482mA
1.52V     -3.531mA   -3.778mA   -2.901mA
1.928V    -3.392mA   -3.623mA   -2.673mA
2.064V    -3.122mA   -2.911mA   -2.51mA
2.132V    -2.646mA   -2.329mA   -2.358mA
2.2V      -1.968mA   -1.858mA   -1.925mA
[GND_clamp]
|Voltage   I(typ)   I(min)   I(max)
-1.1V     -68.65mA   -82.91mA   -64.16mA
-1.054V   -51.26mA   -62.87mA   -50.37mA
-1.008V   -39.63mA   -47.13mA   -42.26mA
-962mV    -32.34mA   -35.82mA   -36.73mA
-916mV    -27.28mA   -28.13mA   -32.02mA
-847mV    -21.22mA   -20.63mA   -25.4mA
-778mV    -15.81mA   -15.27mA   -19.09mA
-663mV    -7.926mA   -8.201mA   -9.607mA
-571mV    -3.246mA   -3.982mA   -3.828mA
-502mV    -1.097mA   -1.819mA   -1.164mA
-410mV    -96.97uA   -374.9uA   -57.53uA
1.1V      0A         0A         0A
[POWER_clamp]
|Voltage   I(typ)   I(min)   I(max)
-1.085V   71.41mA    95.35mA    58.18mA
-1.062V   59.23mA    82.55mA    46.99mA
-1.039V   48.36mA    70.56mA    37.71mA
-1.016V   38.97mA    59.53mA    30.53mA
-970mV    25.17mA    40.76mA    21.88mA
-924mV    17.37mA    26.93mA    17.87mA
-901mV    15.03mA    21.86mA    16.59mA
-855mV    12.01mA    14.79mA    14.5mA
-763mV    8.448mA    8.108mA    10.89mA
-533mV    2.369mA    2.267mA    3.272mA
-349mV    143.9uA    291.4uA    171.3uA
1.1V      0A         0A         0A
[Ramp]
| variable   typ   min   max
dV/dt_r   76.557m/0.199n   78.807m/0.223n   66.720m/0.179n
dV/dt_f   0.119/0.157n   0.116/0.184n   0.115/0.144n
R_load = 50.000
[Rising Waveform]
R_fixture= 50.000
V_fixture= 0.0
V_fixture_min= 0.0
V_fixture_max= 0.0
|time   V(typ)   V(min)   V(max)
0s        2.271uV    12.08uV    1.02uV
413ps     69.29uV    204.3uV    423.2uV
528ps     1.199mV    -496.1uV   48.6mV
611ps     34.84mV    -780.3uV   78.92mV
665ps     61.72mV    11.23mV    90.74mV
747ps     91.47mV    47.51mV    101.1mV
914ps     118.1mV    103.1mV    108.8mV
1.054ns   124.6mV    121.2mV    110.5mV
1.274ns   127.1mV    129.4mV    111.1mV
10ns      127.6mV    131.4mV    111.2mV
[Rising Waveform]
R_fixture= 50.000
V_fixture= 0.550
V_fixture_min= 0.534
V_fixture_max= 0.568
|time   V(typ)   V(min)   V(max)
0s        450.6mV    436.2mV    471.2mV
410ps     450.7mV    436.4mV    473.6mV
509ps     459.2mV    436.2mV    548.7mV
568ps     496mV      438.5mV    582.7mV
618ps     531mV      452.2mV    601.2mV
666ps     558.8mV    480.6mV    612.9mV
754ps     591.4mV    531.6mV    624.7mV
884ps     612.1mV    577mV      631.4mV
1.064ns   620.3mV    598.7mV    633.9mV
10ns      622.6mV    605.9mV    634.5mV
[Falling Waveform]
R_fixture= 50.000
V_fixture= 0.550
V_fixture_min= 0.534
V_fixture_max= 0.568
|time   V(typ)   V(min)   V(max)
0s        622.6mV    605.9mV    634.5mV
390ps     622.7mV    605.8mV    635mV
496ps     619.6mV    606.7mV    538mV
578ps     539.7mV    605.1mV    500.7mV
613ps     514mV      590.3mV    492.2mV
654ps     493.5mV    553.4mV    485.3mV
762ps     466.4mV    482mV      476.2mV
862ps     457.1mV    455.8mV    473.2mV
993ps     452.7mV    443mV      471.8mV
10ns      450.6mV    436.2mV    471.2mV
[Falling Waveform]
R_fixture= 50.000
V_fixture= 0.0
V_fixture_min= 0.0
V_fixture_max= 0.0
|time   V(typ)   V(min)   V(max)
0s        127.6mV    131.3mV    111.2mV
389ps     127.9mV    131.3mV    112.4mV
491ps     126.2mV    132.6mV    47.18mV
565ps     70.69mV    132.4mV    22.2mV
601ps     48.61mV    120.4mV    15.54mV
646ps     30.96mV    86.32mV    10.03mV
702ps     18.07mV    49.73mV    5.85mV
772ps     9.385mV    25.57mV    3.014mV
1.093ns   568.6uV    1.641mV    181.4uV
10ns      2.249uV    12.06uV    1.004uV
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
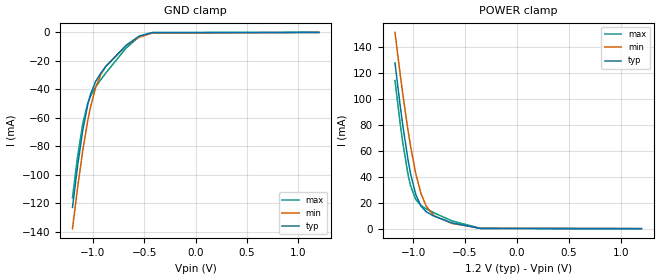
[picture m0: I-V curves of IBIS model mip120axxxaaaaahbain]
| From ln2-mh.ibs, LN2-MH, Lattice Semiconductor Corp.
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|   Model mip120axxxaaaaahbain
[Model] mip120axxxaaaaahbain
Model_type Input
Polarity   Non-Inverting
Enable   Active-High
Vinl =  0.0V
Vinh =  0.400V
C_comp   2.000pF   1.500pF   2.500pF
[Temperature Range]   25.000   0.125k   -40.000
[Voltage Range]   1.200V   1.160V   1.240V
[C Comp Corner]
C_comp   2.000pF   1.500pF   2.500pF
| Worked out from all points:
|   GND clamp passes 1 mA (typ) near -0.49 V on its own axis
|   POWER clamp passes 1 mA (typ) near -0.45 V on its own axis
[GND_clamp]
|Voltage   I(typ)   I(min)   I(max)
-1.2V     -122.8mA   -137.7mA   -116mA
-1.15V    -93.56mA   -108.8mA   -87.01mA
-1.1V     -68.79mA   -82.98mA   -64.13mA
-1.05V    -50.24mA   -61.43mA   -49.5mA
-1.025V   -43.56mA   -52.56mA   -44.86mA
-975mV    -34.44mA   -38.81mA   -38.34mA
-925mV    -28.58mA   -29.69mA   -33.21mA
-875mV    -23.99mA   -23.61mA   -28.43mA
-675mV    -8.907mA   -9.097mA   -10.79mA
-550mV    -2.552mA   -3.344mA   -2.955mA
-425mV    -163.5uA   -531.7uA   -111.6uA
1.2V      0A         0A         0A
[POWER_clamp]
|Voltage   I(typ)   I(min)   I(max)
-1.175V   127.9mA    151.5mA    114.3mA
-1.125V   95.09mA    119.3mA    81.27mA
-1.1V     79.99mA    104.1mA    66.44mA
-1.05V    53.44mA    76.24mA    42.04mA
-1.025V   42.51mA    63.78mA    33.22mA
-975mV    26.4mA     42.63mA    22.6mA
-925mV    17.5mA     27.23mA    17.92mA
-875mV    13.11mA    17.45mA    15.31mA
-800mV    9.677mA    10.04mA    12.26mA
-625mV    4.464mA    4.004mA    6mA
-350mV    147.4uA    295.9uA    176.2uA
1.2V      0A         0A         0A
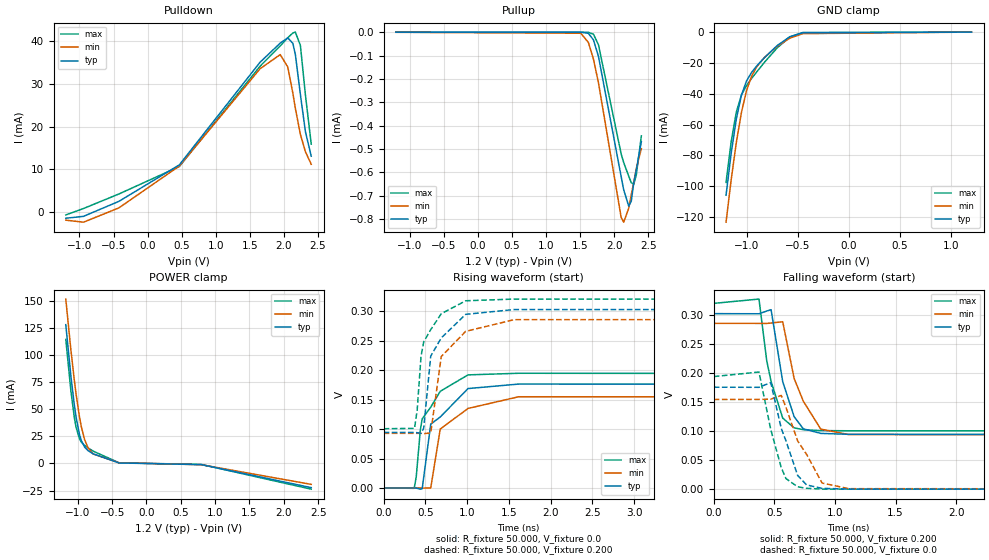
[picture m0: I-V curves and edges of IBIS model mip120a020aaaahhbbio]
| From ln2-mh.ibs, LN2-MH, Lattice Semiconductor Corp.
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|   Model mip120a020aaaahhbbio
[Model] mip120a020aaaahhbbio
| Clamp models do not include dynamic input termination. Please refer to
| the mip120axxxaaaaahbain model for input termination.
Model_type I/O
Polarity   Non-Inverting
Enable   Active-Low
Vinl =  0.0V
Vinh =  0.400V
Vmeas =  0.200V
Cref =  3.000pF
Rref =  50.000
Vref =  0.200V
C_comp   2.000pF   1.500pF   2.500pF
[Temperature Range]   25.000   0.125k   -40.000
[Voltage Range]   1.200V   1.160V   1.240V
[C Comp Corner]
C_comp   2.000pF   1.500pF   2.500pF
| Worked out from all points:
|   slope of the pulldown table from 0 to 0.18 V, typ, clamps not added: 108 ohm
|   GND clamp passes 1 mA (typ) near -0.50 V on its own axis
|   POWER clamp passes 1 mA (typ) near -0.45 V on its own axis
|   rising waveform, R_fixture 50.000, V_fixture 0.0: 20-80 % time 270ps typ, 317ps min, 233ps max; typ from 0 V to 0.176 V
|   rising waveform, R_fixture 50.000, V_fixture 0.200: 20-80 % time 210ps typ, 232ps min, 185ps max; typ from 0.094 V to 0.302 V
|   falling waveform, R_fixture 50.000, V_fixture 0.200: 20-80 % time 133ps typ, 181ps min, 124ps max; typ from 0.302 V to 0.094 V
|   falling waveform, R_fixture 50.000, V_fixture 0.0: 20-80 % time 154ps typ, 212ps min, 142ps max; typ from 0.176 V to 0 V
[Pulldown]
|Voltage   I(typ)   I(min)   I(max)
-1.2V     -1.527mA   -1.986mA   -755.1uA
-941mV    -1.092mA   -2.461mA   749.5uA
-423mV    2.421mA    881.8uA    4.153mA
465mV     11mA       10.73mA    10.61mA
1.649V    35.11mA    33.58mA    34.17mA
1.945V    39.61mA    36.91mA    38.95mA
2.056V    40.84mA    33.99mA    40.86mA
2.13V     39.57mA    27.88mA    41.99mA
2.167V    36.98mA    24.3mA     42.2mA
2.241V    27.54mA    18.16mA    39.08mA
2.315V    18.79mA    14.08mA    27.41mA
2.4V      13.05mA    11.15mA    15.89mA
[Pullup]
|Voltage   I(typ)   I(min)   I(max)
-1.2V     22.97nA    -480.3nA   437.4nA
1.512V    -91nA      -4.458uA   1nA
1.623V    -4.98uA    -43.95uA   -449nA
1.697V    -32.76uA   -114.7uA   -8.476uA
1.771V    -103.4uA   -216.5uA   -53.83uA
2.104V    -618uA     -792.3uA   -520.9uA
2.141V    -674uA     -812.6uA   -557.5uA
2.215V    -744uA     -752.9uA   -615.9uA
2.252V    -722.9uA   -695uA     -643.9uA
2.289V    -643.6uA   -642.2uA   -650.5uA
2.326V    -588.9uA   -582.9uA   -610.3uA
2.4V      -468.1uA   -498.3uA   -443.3uA
[GND_clamp]
|Voltage   I(typ)   I(min)   I(max)
-1.2V     -105.8mA   -123.3mA   -97.49mA
-1.15V    -78.66mA   -95.84mA   -71.19mA
-1.1V     -56.53mA   -71.8mA    -51.99mA
-1.05V    -41mA      -52.28mA   -40.89mA
-1V       -31.72mA   -38mA      -34.69mA
-950mV    -26.11mA   -28.58mA   -30.06mA
-900mV    -21.96mA   -22.52mA   -25.8mA
-825mV    -16.61mA   -16.49mA   -19.64mA
-700mV    -8.748mA   -9.207mA   -10.23mA
-575mV    -2.953mA   -3.893mA   -3.146mA
-450mV    -465.7uA   -997.9uA   -270uA
1.2V      0A         0A         0A
[POWER_clamp]
|Voltage   I(typ)   I(min)   I(max)
-1.175V   127.9mA    151.5mA    114.3mA
-1.1V     79.99mA    104.1mA    66.44mA
-1.05V    53.44mA    76.24mA    42.04mA
-1.025V   42.51mA    63.78mA    33.22mA
-975mV    26.4mA     42.63mA    22.6mA
-950mV    21.18mA    34.18mA    19.82mA
-900mV    14.94mA    21.71mA    16.5mA
-850mV    11.74mA    14.25mA    14.25mA
-775mV    8.814mA    8.66mA     11.3mA
-400mV    446.5uA    628uA      604.6uA
800mV     -1.094mA   -1.192mA   -976.4uA
2.4V      -22.3mA    -19.3mA    -23.72mA
[Ramp]
| variable   typ   min   max
dV/dt_r   0.105/0.270n   92.657m/0.318n   0.116/0.233n
dV/dt_f   0.380/0.109n   0.364/0.142n   0.382/87.205p
R_load = 50.000
[Rising Waveform]
R_fixture= 50.000
V_fixture= 0.0
V_fixture_min= 0.0
V_fixture_max= 0.0
|time   V(typ)   V(min)   V(max)
0s        1.284uV    6.975uV    585nV
366ps     67.93uV    51.66uV    -525uV
390ps     -120.3uV   57.4uV     18.59mV
440ps     -1.956mV   43.53uV    99.09mV
462ps     -1.101mV   -152.1uV   117.3mV
564ps     108.3mV    67.95uV    137.1mV
678ps     120.4mV    100mV      164mV
1.011ns   168.6mV    134.9mV    191.8mV
1.617ns   176.2mV    154.7mV    194.5mV
10ns      175.5mV    154.4mV    193.8mV
[Rising Waveform]
R_fixture= 50.000
V_fixture= 0.200
V_fixture_min= 0.195
V_fixture_max= 0.207
|time   V(typ)   V(min)   V(max)
0s        94.23mV    92.68mV    100.5mV
370ps     94.28mV    92.73mV    101.1mV
402ps     93.78mV    92.73mV    132.6mV
448ps     92.65mV    92.67mV    223.5mV
480ps     101.5mV    92.11mV    247.8mV
564ps     223.6mV    93.42mV    268.5mV
690ps     254.4mV    222.8mV    295.4mV
983ps     294.4mV    265.6mV    317.4mV
1.564ns   302.6mV    285.4mV    320.3mV
10ns      302.1mV    285.4mV    319.8mV
[Falling Waveform]
R_fixture= 50.000
V_fixture= 0.200
V_fixture_min= 0.195
V_fixture_max= 0.207
|time   V(typ)   V(min)   V(max)
0s        302.1mV    285.4mV    319.8mV
373ps     301.9mV    285.3mV    327.2mV
437ps     306.6mV    285.2mV    221.1mV
473ps     308.9mV    286mV      185.3mV
569ps     184.9mV    288.2mV    122.3mV
663ps     124.9mV    190.6mV    105.6mV
739ps     103.8mV    151.4mV    102.3mV
883ps     95.99mV    103.3mV    100.8mV
1.113ns   94.41mV    93.96mV    100.5mV
10ns      94.23mV    92.68mV    100.5mV
[Falling Waveform]
R_fixture= 50.000
V_fixture= 0.0
V_fixture_min= 0.0
V_fixture_max= 0.0
|time   V(typ)   V(min)   V(max)
0s        175.5mV    154.4mV    193.8mV
373ps     175.3mV    154.4mV    201.6mV
470ps     183.5mV    154.9mV    102.9mV
557ps     104.6mV    161.3mV    37.05mV
596ps     82.99mV    140.6mV    18.17mV
692ps     23.67mV    83.17mV    4.083mV
766ps     7.226mV    59.85mV    1.445mV
894ps     1.418mV    10.56mV    253uV
1.114ns   123.6uV    849.4uV    -2.2uV
10ns      2.326uV    8.463uV    1.428uV
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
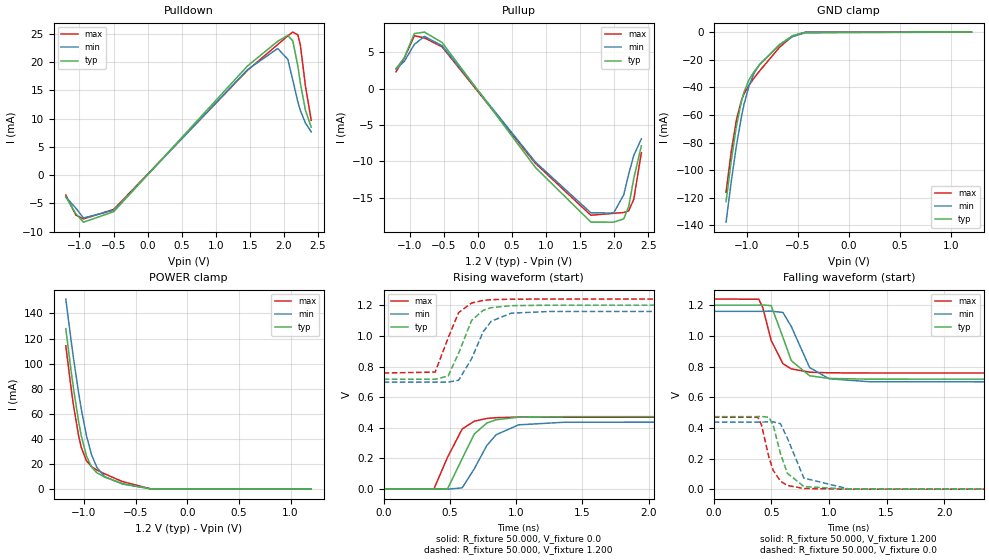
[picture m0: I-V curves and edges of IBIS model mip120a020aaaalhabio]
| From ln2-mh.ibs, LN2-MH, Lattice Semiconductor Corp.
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|   Model mip120a020aaaalhabio
[Model] mip120a020aaaalhabio
Model_type I/O
Polarity   Non-Inverting
Enable   Active-Low
Vinl =  0.550V
Vinh =  0.740V
Vmeas =  0.600V
Cref =  0.0F
Rref =  1.000M
Vref =  0.0V
C_comp   2.000pF   1.500pF   2.500pF
[Temperature Range]   25.000   0.125k   -40.000
[Voltage Range]   1.200V   1.160V   1.240V
[C Comp Corner]
C_comp   2.000pF   1.500pF   2.500pF
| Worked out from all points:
|   slope of the pulldown table from 0 to 0.18 V, typ, clamps not added: 73.8 ohm
|   slope of the pullup table from 0 to 0.18 V, typ, clamps not added: 74.4 ohm
|   GND clamp passes 1 mA (typ) near -0.49 V on its own axis
|   POWER clamp passes 1 mA (typ) near -0.45 V on its own axis
|   rising waveform, R_fixture 50.000, V_fixture 0.0: 20-80 % time 157ps typ, 185ps min, 142ps max; typ from 0 V to 0.473 V
|   rising waveform, R_fixture 50.000, V_fixture 1.200: 20-80 % time 132ps typ, 149ps min, 118ps max; typ from 0.717 V to 1.2 V
|   falling waveform, R_fixture 50.000, V_fixture 1.200: 20-80 % time 135ps typ, 166ps min, 121ps max; typ from 1.2 V to 0.717 V
|   falling waveform, R_fixture 50.000, V_fixture 0.0: 20-80 % time 115ps typ, 135ps min, 107ps max; typ from 0.473 V to 0 V
[Pulldown]
|Voltage   I(typ)   I(min)   I(max)
-1.2V     -3.88mA    -3.873mA   -3.546mA
-1.052V   -6.862mA   -5.868mA   -7.098mA
-941mV    -8.349mA   -7.609mA   -7.769mA
-497mV    -6.484mA   -6.252mA   -6.081mA
1.464V    19.3mA     18.65mA    18.53mA
1.908V    23.68mA    22.41mA    23.1mA
2.056V    24.72mA    20.5mA     24.65mA
2.13V     23.74mA    16.8mA     25.31mA
2.204V    19.27mA    12.93mA    24.82mA
2.241V    16.24mA    11.41mA    23mA
2.315V    11.48mA    9.219mA    15.76mA
2.4V      8.471mA    7.644mA    9.675mA
[Pullup]
|Voltage   I(typ)   I(min)   I(max)
-1.2V     2.721mA    2.737mA    2.316mA
-1.078V   4.25mA     3.739mA    4.183mA
-930mV    7.569mA    6.086mA    7.277mA
-782mV    7.777mA    7.185mA    6.977mA
-523mV    6.35mA     5.903mA    5.753mA
846mV     -10.83mA   -10.09mA   -10.26mA
1.66V     -18.34mA   -17.07mA   -17.4mA
1.993V    -18.35mA   -17.09mA   -17.13mA
2.141V    -17.9mA    -14.6mA    -17.02mA
2.215V    -16.17mA   -11.72mA   -16.78mA
2.289V    -12.34mA   -9.176mA   -15.2mA
2.4V      -7.858mA   -6.895mA   -8.798mA
[GND_clamp]
|Voltage   I(typ)   I(min)   I(max)
-1.2V     -122.8mA   -137.7mA   -116mA
-1.15V    -93.56mA   -108.8mA   -87.01mA
-1.1V     -68.79mA   -82.98mA   -64.13mA
-1.05V    -50.24mA   -61.43mA   -49.5mA
-1.025V   -43.56mA   -52.56mA   -44.86mA
-975mV    -34.44mA   -38.81mA   -38.34mA
-925mV    -28.58mA   -29.69mA   -33.21mA
-875mV    -23.99mA   -23.61mA   -28.43mA
-675mV    -8.907mA   -9.097mA   -10.79mA
-550mV    -2.552mA   -3.344mA   -2.955mA
-425mV    -163.5uA   -531.7uA   -111.6uA
1.2V      0A         0A         0A
[POWER_clamp]
|Voltage   I(typ)   I(min)   I(max)
-1.175V   127.9mA    151.5mA    114.3mA
-1.125V   95.09mA    119.3mA    81.27mA
-1.1V     79.99mA    104.1mA    66.44mA
-1.05V    53.44mA    76.24mA    42.04mA
-1.025V   42.51mA    63.78mA    33.22mA
-975mV    26.4mA     42.63mA    22.6mA
-925mV    17.5mA     27.23mA    17.92mA
-875mV    13.11mA    17.45mA    15.31mA
-800mV    9.677mA    10.04mA    12.26mA
-625mV    4.464mA    4.004mA    6mA
-350mV    147.4uA    295.9uA    176.2uA
1.2V      0A         0A         0A
[Ramp]
| variable   typ   min   max
dV/dt_r   0.284/0.157n   0.263/0.185n   0.282/0.142n
dV/dt_f   0.290/0.136n   0.277/0.166n   0.289/0.121n
R_load = 50.000
[Rising Waveform]
R_fixture= 50.000
V_fixture= 0.0
V_fixture_min= 0.0
V_fixture_max= 0.0
|time   V(typ)   V(min)   V(max)
0s        1.687uV    9.073uV    764.8nV
379ps     155.8uV    125.6uV    770.2uV
482ps     1.177mV    -222.8uV   207.3mV
593ps     199.3mV    8.212mV    392.4mV
684ps     359.6mV    132.6mV    443.2mV
779ps     431.4mV    285mV      461.2mV
849ps     453mV      355mV      466.3mV
1.019ns   469.3mV    419.4mV    469.8mV
1.364ns   472.7mV    436.4mV    470.5mV
10ns      472.9mV    437.5mV    470.5mV
[Rising Waveform]
R_fixture= 50.000
V_fixture= 1.200
V_fixture_min= 1.160
V_fixture_max= 1.240
|time   V(typ)   V(min)   V(max)
0s        716.9mV    698.2mV    757.7mV
389ps     716.9mV    698.4mV    763.5mV
487ps     738.3mV    698.4mV    986.9mV
566ps     887.3mV    710.3mV    1.152V
664ps     1.101V     850.9mV    1.214V
752ps     1.167V     1.028V     1.231V
812ps     1.184V     1.095V     1.236V
962ps     1.197V     1.148V     1.239V
1.252ns   1.2V       1.159V     1.24V
10ns      1.2V       1.16V      1.24V
[Falling Waveform]
R_fixture= 50.000
V_fixture= 1.200
V_fixture_min= 1.160
V_fixture_max= 1.240
|time   V(typ)   V(min)   V(max)
0s        1.2V       1.16V      1.24V
391ps     1.2V       1.16V      1.239V
426ps     1.201V     1.16V      1.183V
498ps     1.197V     1.161V     970.8mV
600ps     991.4mV    1.153V     818.9mV
673ps     838.3mV    1.061V     784.5mV
832ps     739.8mV    793.4mV    763.1mV
1.002ns   722.2mV    720mV      759mV
1.352ns   717.5mV    700.8mV    757.8mV
10ns      716.9mV    698.2mV    757.7mV
[Falling Waveform]
R_fixture= 50.000
V_fixture= 0.0
V_fixture_min= 0.0
V_fixture_max= 0.0
|time   V(typ)   V(min)   V(max)
0s        472.9mV    437.5mV    470.5mV
383ps     473.4mV    437.6mV    468.6mV
414ps     474.2mV    437.7mV    420mV
479ps     468.8mV    438.9mV    207.5mV
516ps     417.2mV    439.3mV    122.7mV
579ps     231.3mV    427.1mV    52.15mV
639ps     103.8mV    333mV      24.13mV
782ps     16.98mV    71.91mV    4.394mV
1.172ns   436.2uV    1.323mV    153.4uV
10ns      1.662uV    9.082uV    708.2nV
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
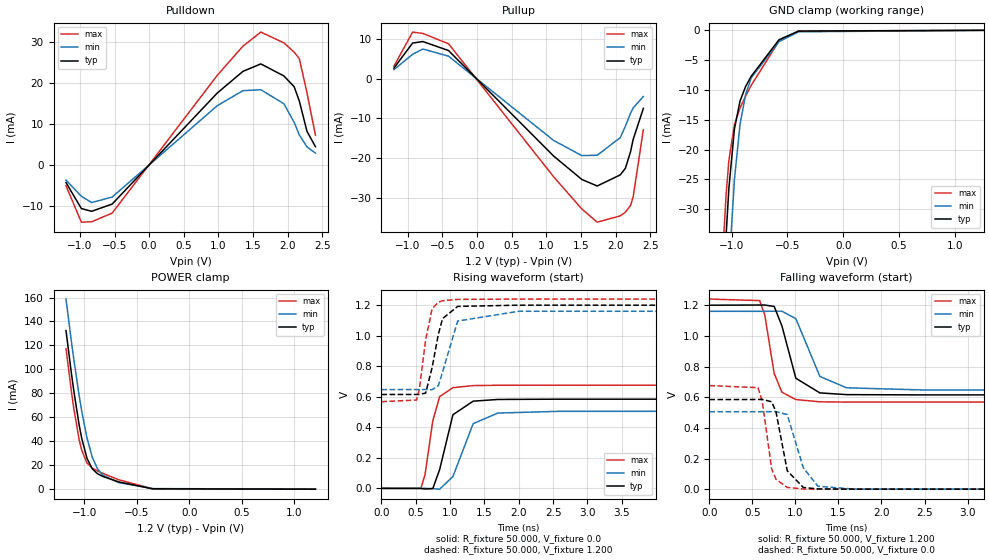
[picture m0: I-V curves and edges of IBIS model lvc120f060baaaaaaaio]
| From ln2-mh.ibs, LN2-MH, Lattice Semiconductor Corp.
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|   Model lvc120f060baaaaaaaio
[Model] lvc120f060baaaaaaaio
Model_type I/O
Polarity   Non-Inverting
Enable   Active-Low
Vinl =  0.420V
Vinh =  0.780V
Vmeas =  0.600V
Cref =  0.0F
Rref =  1.000M
Vref =  0.0V
C_comp   2.000pF   1.500pF   2.500pF
[Temperature Range]   25.000   0.125k   -40.000
[Voltage Range]   1.200V   1.160V   1.240V
[C Comp Corner]
C_comp   2.000pF   1.500pF   2.500pF
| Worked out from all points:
|   slope of the pulldown table from 0 to 0.18 V, typ, clamps not added: 53.5 ohm
|   slope of the pullup table from 0 to 0.18 V, typ, clamps not added: 54.5 ohm
|   GND clamp passes 1 mA (typ) near -0.54 V on its own axis
|   POWER clamp passes 1 mA (typ) near -0.43 V on its own axis
|   rising waveform, R_fixture 50.000, V_fixture 0.0: 20-80 % time 182ps typ, 245ps min, 143ps max; typ from 0 V to 0.584 V
|   rising waveform, R_fixture 50.000, V_fixture 1.200: 20-80 % time 155ps typ, 184ps min, 122ps max; typ from 0.615 V to 1.2 V
|   falling waveform, R_fixture 50.000, V_fixture 1.200: 20-80 % time 162ps typ, 218ps min, 125ps max; typ from 1.2 V to 0.615 V
|   falling waveform, R_fixture 50.000, V_fixture 0.0: 20-80 % time 119ps typ, 147ps min, 99.3ps max; typ from 0.584 V to 0 V
[Pulldown]
|Voltage   I(typ)   I(min)   I(max)
-1.2V     -4.215mA   -3.606mA   -5.005mA
-978mV    -10.54mA   -7.565mA   -13.86mA
-830mV    -11.21mA   -9.068mA   -13.76mA
-534mV    -9.444mA   -7.737mA   -11.65mA
983mV     17.59mA    14.51mA    21.91mA
1.353V    22.87mA    18.17mA    29mA
1.612V    24.69mA    18.4mA     32.44mA
1.945V    21.75mA    14.98mA    29.81mA
2.093V    19.13mA    10.46mA    27.56mA
2.167V    15.67mA    7.395mA    25.98mA
2.278V    8.261mA    4.461mA    17.68mA
2.4V      4.525mA    2.971mA    7.343mA
[Pullup]
|Voltage   I(typ)   I(min)   I(max)
-1.2V     2.727mA    2.327mA    3.207mA
-930mV    9.072mA    6.215mA    11.83mA
-782mV    9.439mA    7.547mA    11.49mA
-412mV    7.165mA    5.748mA    8.874mA
1.105V    -19.5mA    -15.56mA   -24.74mA
1.512V    -25.42mA   -19.39mA   -32.88mA
1.734V    -27.07mA   -19.3mA    -36.22mA
2.067V    -24.26mA   -14.84mA   -34.62mA
2.141V    -22.58mA   -11.94mA   -33.68mA
2.215V    -18.42mA   -8.669mA   -31.99mA
2.252V    -15.35mA   -7.355mA   -29.89mA
2.4V      -7.451mA   -4.454mA   -12.83mA
[GND_clamp]
|Voltage   I(typ)   I(min)   I(max)
-1.2V     -115.8mA   -133.1mA   -106.7mA
-1.1V     -56.13mA   -73.79mA   -46.76mA
-1.075V   -44.35mA   -61.25mA   -35.93mA
-1.05V    -34.4mA    -49.96mA   -27.58mA
-1.025V   -26.48mA   -40.08mA   -21.8mA
-975mV    -16.5mA    -24.97mA   -15.79mA
-925mV    -11.85mA   -15.76mA   -13.02mA
-875mV    -9.422mA   -10.76mA   -11.03mA
-825mV    -7.705mA   -7.983mA   -9.226mA
-575mV    -1.568mA   -1.879mA   -1.797mA
-400mV    -127.7uA   -246.9uA   -111uA
1.26V     0A         0A         0A
[POWER_clamp]
|Voltage   I(typ)   I(min)   I(max)
-1.175V   132.4mA    158.7mA    117.3mA
-1.125V   97.68mA    124.2mA    82.53mA
-1.1V     81.71mA    108mA      66.96mA
-1.05V    53.72mA    78.17mA    41.46mA
-1.025V   42.29mA    64.94mA    32.4mA
-975mV    25.73mA    42.64mA    21.9mA
-925mV    17mA       26.75mA    17.58mA
-875mV    12.91mA    17.01mA    15.19mA
-825mV    10.65mA    11.68mA    13.24mA
-675mV    6.1mA      5.538mA    7.913mA
-350mV    294.7uA    490.5uA    329uA
1.2V      0A         0A         0A
[Ramp]
| variable   typ   min   max
dV/dt_r   0.351/0.183n   0.303/0.246n   0.405/0.144n
dV/dt_f   0.351/0.162n   0.308/0.219n   0.403/0.126n
R_load = 50.000
[Rising Waveform]
R_fixture= 50.000
V_fixture= 0.0
V_fixture_min= 0.0
V_fixture_max= 0.0
|time   V(typ)   V(min)   V(max)
0s        29.47nV    1.263uV    3.133nV
575ps     -852.5uV   19.13uV    897uV
635ps     -3.9mV     74.22uV    90.51mV
748ps     -1.208mV   -1.805mV   443.2mV
848ps     123.8mV    -5.179mV   601.3mV
1.041ns   482.3mV    77.84mV    659.9mV
1.336ns   571.3mV    424.1mV    673.2mV
1.696ns   582.4mV    493.4mV    675.4mV
2.606ns   584.3mV    504.8mV    675.6mV
50ns      584.3mV    505.1mV    675.7mV
[Rising Waveform]
R_fixture= 50.000
V_fixture= 1.200
V_fixture_min= 1.160
V_fixture_max= 1.240
|time   V(typ)   V(min)   V(max)
0s        614.9mV    647mV      567.8mV
511ps     615.3mV    647.2mV    578.6mV
551ps     615.1mV    647.3mV    645.5mV
644ps     624.3mV    647.3mV    975.1mV
738ps     791.6mV    646.4mV    1.176V
829ps     1.01V      672.9mV    1.22V
890ps     1.112V     762.3mV    1.229V
1.11ns    1.192V     1.096V     1.238V
1.998ns   1.2V       1.16V      1.24V
50ns      1.2V       1.16V      1.24V
[Falling Waveform]
R_fixture= 50.000
V_fixture= 1.200
V_fixture_min= 1.160
V_fixture_max= 1.240
|time   V(typ)   V(min)   V(max)
0s        1.2V       1.16V      1.24V
585ps     1.201V     1.16V      1.23V
645ps     1.201V     1.16V      1.133V
753ps     1.192V     1.161V     754.9mV
843ps     1.065V     1.161V     632.5mV
1.005ns   723.3mV    1.112V     584.6mV
1.284ns   627.9mV    735.5mV    569.7mV
1.594ns   616.7mV    661.1mV    568.1mV
2.474ns   614.9mV    647.2mV    567.8mV
50ns      614.9mV    646.9mV    567.8mV
[Falling Waveform]
R_fixture= 50.000
V_fixture= 0.0
V_fixture_min= 0.0
V_fixture_max= 0.0
|time   V(typ)   V(min)   V(max)
0s        584.3mV    505.1mV    675.7mV
565ps     584.9mV    505.1mV    662.1mV
615ps     585.6mV    505mV      572.4mV
724ps     569.9mV    505.8mV    131.6mV
774ps     504.8mV    506.1mV    64.4mV
905ps     120.2mV    486.3mV    11.35mV
1.091ns   11.26mV    140.2mV    1.173mV
1.261ns   1.665mV    19.13mV    216.8uV
1.681ns   87.43uV    498.6uV    21.06uV
50ns      1.245uV    2.599uV    687.3nV
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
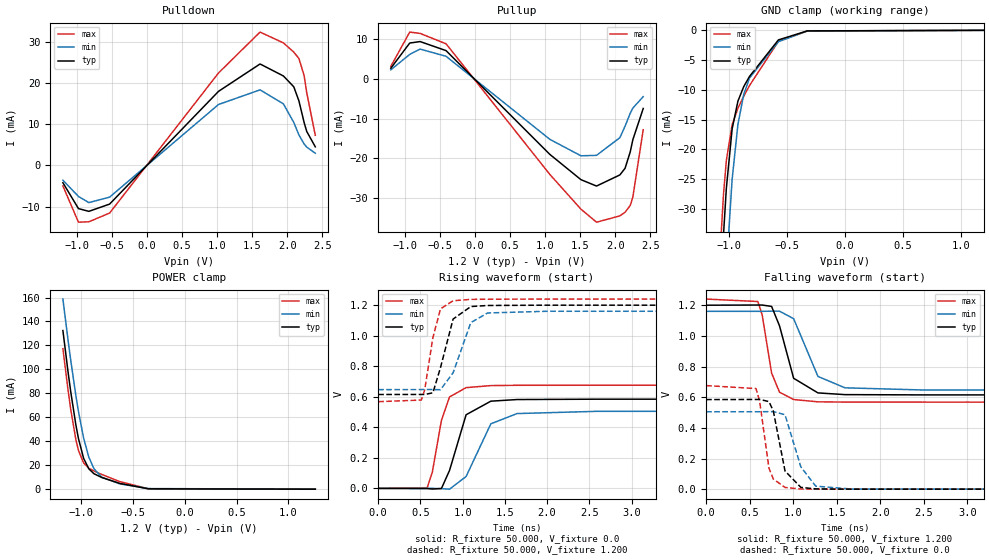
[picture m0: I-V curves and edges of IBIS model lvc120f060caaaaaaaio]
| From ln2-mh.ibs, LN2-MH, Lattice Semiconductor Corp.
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|   Model lvc120f060caaaaaaaio
[Model] lvc120f060caaaaaaaio
Model_type I/O
Polarity   Non-Inverting
Enable   Active-Low
Vinl =  0.420V
Vinh =  0.780V
Vmeas =  0.600V
Cref =  0.0F
Rref =  1.000M
Vref =  0.0V
C_comp   2.000pF   1.500pF   2.500pF
[Temperature Range]   25.000   0.125k   -40.000
[Voltage Range]   1.200V   1.160V   1.240V
[C Comp Corner]
C_comp   2.000pF   1.500pF   2.500pF
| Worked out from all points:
|   slope of the pulldown table from 0 to 0.18 V, typ, clamps not added: 54.3 ohm
|   slope of the pullup table from 0 to 0.18 V, typ, clamps not added: 53.8 ohm
|   GND clamp passes 1 mA (typ) near -0.53 V on its own axis
|   POWER clamp passes 1 mA (typ) near -0.43 V on its own axis
|   rising waveform, R_fixture 50.000, V_fixture 0.0: 20-80 % time 182ps typ, 245ps min, 143ps max; typ from 0 V to 0.584 V
|   rising waveform, R_fixture 50.000, V_fixture 1.200: 20-80 % time 155ps typ, 184ps min, 122ps max; typ from 0.615 V to 1.2 V
|   falling waveform, R_fixture 50.000, V_fixture 1.200: 20-80 % time 162ps typ, 218ps min, 125ps max; typ from 1.2 V to 0.615 V
|   falling waveform, R_fixture 50.000, V_fixture 0.0: 20-80 % time 119ps typ, 147ps min, 99.3ps max; typ from 0.584 V to 0 V
[Pulldown]
|Voltage   I(typ)   I(min)   I(max)
-1.2V     -4.202mA   -3.596mA   -4.99mA
-978mV    -10.5mA    -7.543mA   -13.81mA
-830mV    -11.17mA   -9.041mA   -13.71mA
-534mV    -9.404mA   -7.714mA   -11.59mA
1.02V     18.04mA    14.84mA    22.52mA
1.612V    24.7mA     18.4mA     32.46mA
1.945V    21.78mA    14.99mA    29.84mA
2.093V    19.15mA    10.47mA    27.59mA
2.167V    15.69mA    7.404mA    26.01mA
2.241V    10.42mA    5.214mA    21.84mA
2.278V    8.273mA    4.468mA    17.7mA
2.4V      4.531mA    2.975mA    7.352mA
[Pullup]
|Voltage   I(typ)   I(min)   I(max)
-1.2V     2.734mA    2.332mA    3.215mA
-930mV    9.095mA    6.229mA    11.86mA
-782mV    9.464mA    7.564mA    11.52mA
-412mV    7.177mA    5.748mA    8.9mA
1.068V    -19.03mA   -15.23mA   -24.09mA
1.512V    -25.42mA   -19.39mA   -32.87mA
1.734V    -27.03mA   -19.28mA   -36.16mA
2.067V    -24.22mA   -14.81mA   -34.57mA
2.141V    -22.55mA   -11.92mA   -33.64mA
2.215V    -18.4mA    -8.652mA   -31.94mA
2.252V    -15.33mA   -7.341mA   -29.85mA
2.4V      -7.439mA   -4.445mA   -12.81mA
[GND_clamp]
|Voltage   I(typ)   I(min)   I(max)
-1.2V     -115.8mA   -133.1mA   -106.7mA
-1.1V     -56.15mA   -73.8mA    -46.79mA
-1.075V   -44.37mA   -61.27mA   -35.96mA
-1.05V    -34.42mA   -49.98mA   -27.62mA
-1.025V   -26.5mA    -40.1mA    -21.84mA
-975mV    -16.54mA   -25mA      -15.84mA
-925mV    -11.89mA   -15.79mA   -13.07mA
-875mV    -9.459mA   -10.78mA   -11.08mA
-825mV    -7.743mA   -8.01mA    -9.276mA
-575mV    -1.608mA   -1.904mA   -1.854mA
-325mV    -94.59uA   -107.1uA   -110.5uA
1.2V      0A         0A         0A
[POWER_clamp]
|Voltage   I(typ)   I(min)   I(max)
-1.175V   132.4mA    158.7mA    117.3mA
-1.125V   97.67mA    124.2mA    82.52mA
-1.1V     81.7mA     108mA      66.95mA
-1.05V    53.71mA    78.17mA    41.44mA
-1.025V   42.27mA    64.93mA    32.38mA
-975mV    25.71mA    42.63mA    21.87mA
-925mV    16.98mA    26.74mA    17.54mA
-875mV    12.89mA    17mA       15.15mA
-800mV    9.742mA    10mA       12.28mA
-625mV    4.793mA    4.396mA    6.256mA
-350mV    291.9uA    500.3uA    309.5uA
1.26V     0A         0A         0A
[Ramp]
| variable   typ   min   max
dV/dt_r   0.351/0.183n   0.303/0.245n   0.405/0.144n
dV/dt_f   0.351/0.162n   0.308/0.219n   0.403/0.126n
R_load = 50.000
[Rising Waveform]
R_fixture= 50.000
V_fixture= 0.0
V_fixture_min= 0.0
V_fixture_max= 0.0
|time   V(typ)   V(min)   V(max)
0s        29.47nV    1.263uV    3.133nV
581ps     -1.17mV    25.18uV    4.545mV
641ps     -4.166mV   86.32uV    106.1mV
749ps     -758.5uV   -1.845mV   445.9mV
845ps     117.8mV    -5.095mV   599mV
1.041ns   482.3mV    77.84mV    659.9mV
1.334ns   571.2mV    423mV      673.2mV
1.644ns   581.9mV    490mV      675.3mV
2.594ns   584.3mV    504.8mV    675.6mV
50ns      584.3mV    505.1mV    675.7mV
[Rising Waveform]
R_fixture= 50.000
V_fixture= 1.200
V_fixture_min= 1.160
V_fixture_max= 1.240
|time   V(typ)   V(min)   V(max)
0s        614.9mV    647mV      567.8mV
511ps     615.3mV    647.2mV    578.6mV
551ps     615.1mV    647.3mV    645.5mV
648ps     626.1mV    647.3mV    988.3mV
738ps     791.5mV    646.4mV    1.176V
887ps     1.109V     756.9mV    1.229V
1.097ns   1.191V     1.086V     1.238V
1.297ns   1.198V     1.149V     1.239V
2ns       1.2V       1.16V      1.24V
50ns      1.2V       1.16V      1.24V
[Falling Waveform]
R_fixture= 50.000
V_fixture= 1.200
V_fixture_min= 1.160
V_fixture_max= 1.240
|time   V(typ)   V(min)   V(max)
0s        1.2V       1.16V      1.24V
594ps     1.201V     1.16V      1.224V
644ps     1.201V     1.16V      1.136V
752ps     1.192V     1.161V     757.3mV
843ps     1.065V     1.161V     632.5mV
1.005ns   723.3mV    1.112V     584.6mV
1.284ns   627.9mV    735.5mV    569.7mV
1.594ns   616.7mV    661.1mV    568.1mV
2.474ns   614.9mV    647.2mV    567.8mV
50ns      614.9mV    646.9mV    567.8mV
[Falling Waveform]
R_fixture= 50.000
V_fixture= 0.0
V_fixture_min= 0.0
V_fixture_max= 0.0
|time   V(typ)   V(min)   V(max)
0s        584.3mV    505.1mV    675.7mV
573ps     585.1mV    505.1mV    656mV
614ps     585.6mV    505mV      576.1mV
722ps     571mV      505.8mV    136.3mV
772ps     509.5mV    506.1mV    66.38mV
906ps     118.7mV    485.5mV    11.22mV
1.088ns   11.67mV    145.1mV    1.216mV
1.258ns   1.718mV    19.8mV     222.8uV
1.677ns   88.9uV     509.7uV    21.32uV
50ns      1.239uV    2.599uV    686.3nV
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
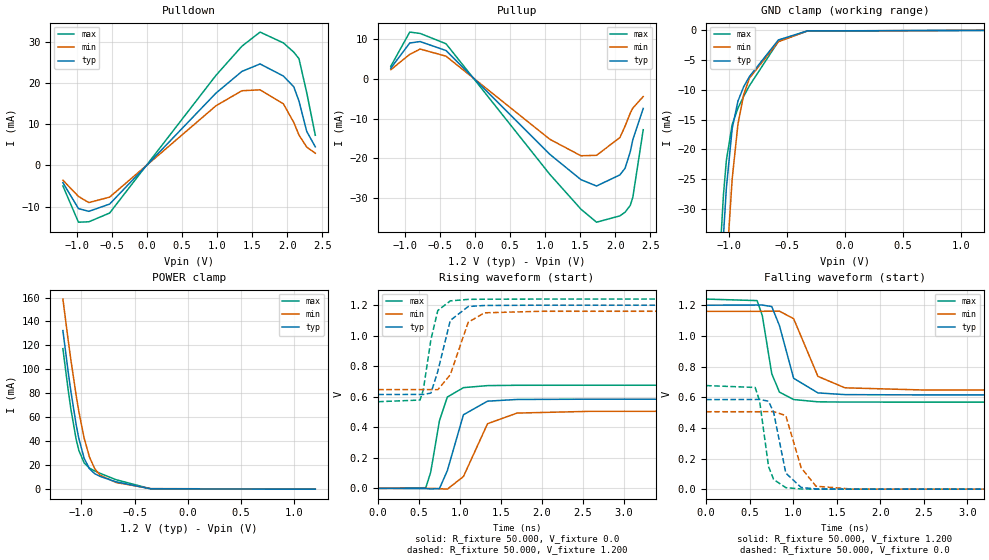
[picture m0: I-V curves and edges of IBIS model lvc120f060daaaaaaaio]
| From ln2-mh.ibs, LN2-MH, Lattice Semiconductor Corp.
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|   Model lvc120f060daaaaaaaio
[Model] lvc120f060daaaaaaaio
Model_type I/O
Polarity   Non-Inverting
Enable   Active-Low
Vinl =  0.420V
Vinh =  0.780V
Vmeas =  0.600V
Cref =  0.0F
Rref =  1.000M
Vref =  0.0V
C_comp   2.000pF   1.500pF   2.500pF
[Temperature Range]   25.000   0.125k   -40.000
[Voltage Range]   1.200V   1.160V   1.240V
[C Comp Corner]
C_comp   2.000pF   1.500pF   2.500pF
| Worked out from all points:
|   slope of the pulldown table from 0 to 0.18 V, typ, clamps not added: 54.3 ohm
|   slope of the pullup table from 0 to 0.18 V, typ, clamps not added: 54.5 ohm
|   GND clamp passes 1 mA (typ) near -0.53 V on its own axis
|   POWER clamp passes 1 mA (typ) near -0.43 V on its own axis
|   rising waveform, R_fixture 50.000, V_fixture 0.0: 20-80 % time 182ps typ, 245ps min, 143ps max; typ from 0 V to 0.584 V
|   rising waveform, R_fixture 50.000, V_fixture 1.200: 20-80 % time 155ps typ, 184ps min, 122ps max; typ from 0.615 V to 1.2 V
|   falling waveform, R_fixture 50.000, V_fixture 1.200: 20-80 % time 162ps typ, 218ps min, 125ps max; typ from 1.2 V to 0.615 V
|   falling waveform, R_fixture 50.000, V_fixture 0.0: 20-80 % time 119ps typ, 147ps min, 99.3ps max; typ from 0.584 V to 0 V
[Pulldown]
|Voltage   I(typ)   I(min)   I(max)
-1.2V     -4.202mA   -3.596mA   -4.99mA
-978mV    -10.5mA    -7.543mA   -13.81mA
-830mV    -11.17mA   -9.041mA   -13.71mA
-534mV    -9.404mA   -7.714mA   -11.59mA
983mV     17.59mA    14.51mA    21.91mA
1.353V    22.87mA    18.17mA    29mA
1.612V    24.69mA    18.4mA     32.44mA
1.945V    21.75mA    14.98mA    29.81mA
2.093V    19.13mA    10.46mA    27.56mA
2.167V    15.67mA    7.395mA    25.98mA
2.278V    8.261mA    4.461mA    17.68mA
2.4V      4.525mA    2.971mA    7.343mA
[Pullup]
|Voltage   I(typ)   I(min)   I(max)
-1.2V     2.727mA    2.327mA    3.207mA
-930mV    9.072mA    6.215mA    11.83mA
-782mV    9.439mA    7.547mA    11.49mA
-412mV    7.165mA    5.748mA    8.874mA
1.068V    -19.03mA   -15.23mA   -24.09mA
1.512V    -25.42mA   -19.39mA   -32.87mA
1.734V    -27.03mA   -19.28mA   -36.16mA
2.067V    -24.22mA   -14.81mA   -34.57mA
2.141V    -22.55mA   -11.92mA   -33.64mA
2.215V    -18.4mA    -8.652mA   -31.94mA
2.252V    -15.33mA   -7.341mA   -29.85mA
2.4V      -7.439mA   -4.445mA   -12.81mA
[GND_clamp]
|Voltage   I(typ)   I(min)   I(max)
-1.2V     -115.8mA   -133.1mA   -106.7mA
-1.1V     -56.15mA   -73.8mA    -46.79mA
-1.075V   -44.37mA   -61.27mA   -35.96mA
-1.05V    -34.42mA   -49.98mA   -27.62mA
-1.025V   -26.5mA    -40.1mA    -21.84mA
-975mV    -16.54mA   -25mA      -15.84mA
-925mV    -11.89mA   -15.79mA   -13.07mA
-875mV    -9.459mA   -10.78mA   -11.08mA
-825mV    -7.743mA   -8.01mA    -9.276mA
-575mV    -1.608mA   -1.904mA   -1.854mA
-325mV    -94.59uA   -107.1uA   -110.5uA
1.2V      -90.03nA   2.134uA    -12.11uA
[POWER_clamp]
|Voltage   I(typ)   I(min)   I(max)
-1.175V   132.4mA    158.7mA    117.3mA
-1.125V   97.68mA    124.2mA    82.53mA
-1.1V     81.71mA    108mA      66.96mA
-1.05V    53.72mA    78.17mA    41.46mA
-1.025V   42.29mA    64.94mA    32.4mA
-975mV    25.73mA    42.64mA    21.9mA
-925mV    17mA       26.75mA    17.58mA
-875mV    12.91mA    17.01mA    15.19mA
-825mV    10.65mA    11.68mA    13.24mA
-675mV    6.1mA      5.538mA    7.913mA
-350mV    294.7uA    490.5uA    329uA
1.2V      0A         0A         12.42uA
[Ramp]
| variable   typ   min   max
dV/dt_r   0.351/0.183n   0.303/0.246n   0.405/0.144n
dV/dt_f   0.351/0.162n   0.308/0.218n   0.403/0.126n
R_load = 50.000
[Rising Waveform]
R_fixture= 50.000
V_fixture= 0.0
V_fixture_min= 0.0
V_fixture_max= 0.0
|time   V(typ)   V(min)   V(max)
0s        29.47nV    1.263uV    3.133nV
581ps     -1.176mV   25.09uV    4.572mV
641ps     -4.17mV    86.21uV    106.1mV
748ps     -1.168mV   -1.802mV   443.3mV
844ps     115.9mV    -5.065mV   598.3mV
1.041ns   482.3mV    77.76mV    659.9mV
1.335ns   571.3mV    423.5mV    673.2mV
1.695ns   582.4mV    493.3mV    675.4mV
2.595ns   584.3mV    504.8mV    675.6mV
50ns      584.3mV    505.1mV    675.7mV
[Rising Waveform]
R_fixture= 50.000
V_fixture= 1.200
V_fixture_min= 1.160
V_fixture_max= 1.240
|time   V(typ)   V(min)   V(max)
0s        614.9mV    647mV      567.8mV
511ps     615.3mV    647.2mV    578.6mV
551ps     615.1mV    647.3mV    645.5mV
644ps     624.3mV    647.3mV    975.1mV
728ps     766.9mV    646.3mV    1.165V
880ps     1.1V       744.1mV    1.228V
1.099ns   1.191V     1.088V     1.238V
1.299ns   1.198V     1.15V      1.239V
1.998ns   1.2V       1.16V      1.24V
50ns      1.2V       1.16V      1.24V
[Falling Waveform]
R_fixture= 50.000
V_fixture= 1.200
V_fixture_min= 1.160
V_fixture_max= 1.240
|time   V(typ)   V(min)   V(max)
0s        1.2V       1.16V      1.24V
585ps     1.201V     1.16V      1.23V
645ps     1.201V     1.16V      1.133V
754ps     1.191V     1.161V     752.6mV
842ps     1.067V     1.161V     633.1mV
1.005ns   723.3mV    1.112V     584.6mV
1.284ns   627.9mV    735.6mV    569.7mV
1.594ns   616.7mV    661.1mV    568.1mV
2.474ns   614.9mV    647.2mV    567.8mV
50ns      614.9mV    646.9mV    567.8mV
[Falling Waveform]
R_fixture= 50.000
V_fixture= 0.0
V_fixture_min= 0.0
V_fixture_max= 0.0
|time   V(typ)   V(min)   V(max)
0s        584.3mV    505.1mV    675.7mV
563ps     584.9mV    505.1mV    663.4mV
614ps     585.6mV    505mV      576.1mV
717ps     573.4mV    505.7mV    146.9mV
775ps     502.5mV    506.1mV    63.66mV
915ps     105.1mV    479.9mV    9.961mV
1.091ns   11.26mV    140.2mV    1.175mV
1.261ns   1.665mV    19.13mV    217.1uV
1.681ns   87.43uV    498.6uV    21.07uV
50ns      1.244uV    2.599uV    678.5nV
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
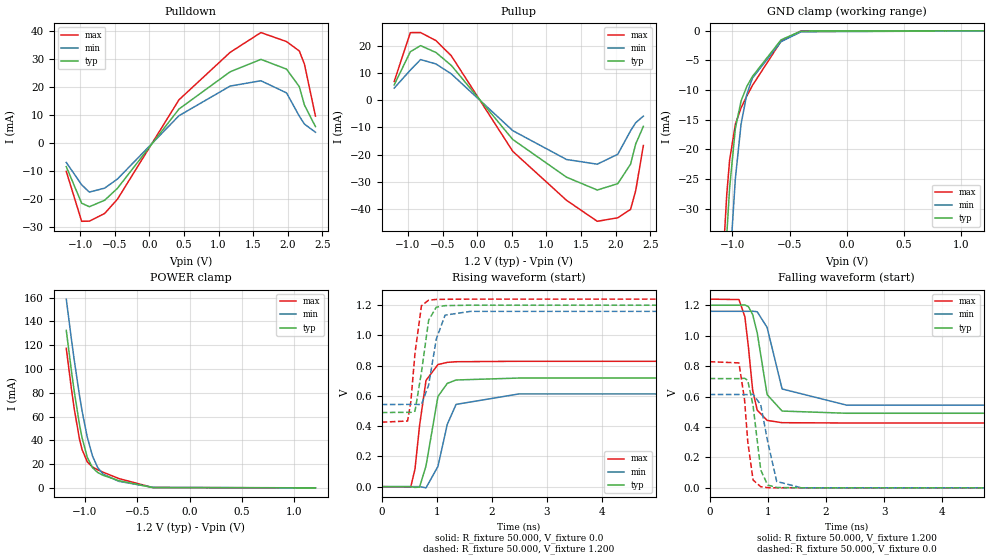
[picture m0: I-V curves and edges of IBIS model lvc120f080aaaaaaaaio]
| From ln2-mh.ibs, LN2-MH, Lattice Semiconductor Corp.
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|   Model lvc120f080aaaaaaaaio
[Model] lvc120f080aaaaaaaaio
Model_type I/O
Polarity   Non-Inverting
Enable   Active-Low
Vinl =  0.420V
Vinh =  0.780V
Vmeas =  0.600V
Cref =  0.0F
Rref =  1.000M
Vref =  0.0V
C_comp   2.000pF   1.500pF   2.500pF
[Temperature Range]   25.000   0.125k   -40.000
[Voltage Range]   1.200V   1.160V   1.240V
[C Comp Corner]
C_comp   2.000pF   1.500pF   2.500pF
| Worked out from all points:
|   slope of the pulldown table from 0 to 0.18 V, typ, clamps not added: 31.6 ohm
|   slope of the pullup table from 0 to 0.18 V, typ, clamps not added: 31.6 ohm
|   GND clamp passes 1 mA (typ) near -0.54 V on its own axis
|   POWER clamp passes 1 mA (typ) near -0.43 V on its own axis
|   rising waveform, R_fixture 50.000, V_fixture 0.0: 20-80 % time 195ps typ, 251ps min, 156ps max; typ from 0 V to 0.718 V
|   rising waveform, R_fixture 50.000, V_fixture 1.200: 20-80 % time 148ps typ, 179ps min, 118ps max; typ from 0.49 V to 1.2 V
|   falling waveform, R_fixture 50.000, V_fixture 1.200: 20-80 % time 172ps typ, 226ps min, 136ps max; typ from 1.2 V to 0.49 V
|   falling waveform, R_fixture 50.000, V_fixture 0.0: 20-80 % time 134ps typ, 164ps min, 112ps max; typ from 0.718 V to 0 V
[Pulldown]
|Voltage   I(typ)   I(min)   I(max)
-1.2V     -8.325mA   -6.797mA   -10.02mA
-978mV    -21.37mA   -14.81mA   -27.83mA
-867mV    -22.62mA   -17.41mA   -27.77mA
-645mV    -20.31mA   -15.98mA   -25.02mA
-460mV    -16.04mA   -12.72mA   -19.91mA
428mV     12.25mA    9.863mA    15.54mA
1.168V    25.56mA    20.45mA    32.5mA
1.612V    29.98mA    22.35mA    39.55mA
1.982V    26.5mA     18.02mA    36.34mA
2.167V    20.23mA    9.701mA    32.98mA
2.241V    13.65mA    6.883mA    28.26mA
2.4V      5.97mA     3.966mA    9.719mA
[Pullup]
|Voltage   I(typ)   I(min)   I(max)
-1.2V     5.601mA    4.423mA    6.866mA
-967mV    17.82mA    11.05mA    24.85mA
-819mV    20.07mA    14.93mA    24.87mA
-597mV    17.54mA    13.33mA    21.92mA
-375mV    12.79mA    9.668mA    16.33mA
513mV     -14.47mA   -11.22mA   -18.83mA
1.29V     -28.35mA   -21.84mA   -36.86mA
1.734V    -33.07mA   -23.56mA   -44.58mA
2.03V     -30.73mA   -19.92mA   -43.29mA
2.215V    -23.55mA   -11.28mA   -40.2mA
2.289V    -16.13mA   -8.3mA     -33.3mA
2.4V      -9.659mA   -5.883mA   -16.7mA
[GND_clamp]
|Voltage   I(typ)   I(min)   I(max)
-1.2V     -115.8mA   -133.1mA   -106.7mA
-1.1V     -56.13mA   -73.78mA   -46.76mA
-1.075V   -44.35mA   -61.25mA   -35.92mA
-1.05V    -34.39mA   -49.96mA   -27.58mA
-1.025V   -26.47mA   -40.07mA   -21.79mA
-975mV    -16.49mA   -24.96mA   -15.78mA
-925mV    -11.84mA   -15.75mA   -13.01mA
-875mV    -9.407mA   -10.74mA   -11.02mA
-825mV    -7.688mA   -7.964mA   -9.21mA
-575mV    -1.526mA   -1.839mA   -1.756mA
-400mV    -41.92uA   -170.5uA   -22.66uA
1.2V      2.666pA    5.169nA    0A
[POWER_clamp]
|Voltage   I(typ)   I(min)   I(max)
-1.175V   132.4mA    158.7mA    117.3mA
-1.125V   97.66mA    124.2mA    82.52mA
-1.1V     81.7mA     108mA      66.94mA
-1.05V    53.7mA     78.16mA    41.43mA
-1.025V   42.27mA    64.92mA    32.37mA
-975mV    25.7mA     42.62mA    21.86mA
-925mV    16.96mA    26.72mA    17.53mA
-875mV    12.88mA    16.98mA    15.14mA
-825mV    10.61mA    11.65mA    13.19mA
-675mV    6.055mA    5.5mA      7.862mA
-350mV    219.1uA    435.6uA    237.4uA
1.2V      0A         0A         0A
[Ramp]
| variable   typ   min   max
dV/dt_r   0.431/0.196n   0.368/0.252n   0.497/0.157n
dV/dt_f   0.426/0.173n   0.370/0.227n   0.488/0.136n
R_load = 50.000
[Rising Waveform]
R_fixture= 50.000
V_fixture= 0.0
V_fixture_min= 0.0
V_fixture_max= 0.0
|time   V(typ)   V(min)   V(max)
0s        21.16nV    961.3nV    2.149nV
527ps     245.9uV    -22.84uV   -2.504mV
605ps     -5.37mV    58.61uV    117.2mV
688ps     -2.927mV   117.9uV    404.7mV
805ps     137.1mV    -8.057mV   702.6mV
1.022ns   596.2mV    133.7mV    807.3mV
1.192ns   683mV      412.2mV    821.8mV
1.352ns   705.3mV    544mV      826mV
2.492ns   718.1mV    612.8mV    828.9mV
50ns      718.2mV    613.2mV    828.9mV
[Rising Waveform]
R_fixture= 50.000
V_fixture= 1.200
V_fixture_min= 1.160
V_fixture_max= 1.240
|time   V(typ)   V(min)   V(max)
0s        490.1mV    543mV      426.3mV
470ps     491.4mV    543.8mV    433.9mV
530ps     491.3mV    544mV      564.1mV
605ps     499.7mV    544.2mV    884.4mV
722ps     756.4mV    542.6mV    1.196V
853ps     1.101V     672.4mV    1.233V
993ps     1.187V     977.4mV    1.238V
1.152ns   1.197V     1.134V     1.239V
1.613ns   1.2V       1.159V     1.24V
50ns      1.2V       1.16V      1.24V
[Falling Waveform]
R_fixture= 50.000
V_fixture= 1.200
V_fixture_min= 1.160
V_fixture_max= 1.240
|time   V(typ)   V(min)   V(max)
0s        1.2V       1.16V      1.24V
504ps     1.2V       1.16V      1.237V
605ps     1.202V     1.16V      1.125V
665ps     1.191V     1.16V      929.1mV
739ps     1.139V     1.161V     641.6mV
817ps     1.019V     1.157V     511mV
987ps     612.8mV    1.054V     443.3mV
1.245ns   504.6mV    649.7mV    428.1mV
2.355ns   490.1mV    543.4mV    426.2mV
50ns      490mV      543mV      426.2mV
[Falling Waveform]
R_fixture= 50.000
V_fixture= 0.0
V_fixture_min= 0.0
V_fixture_max= 0.0
|time   V(typ)   V(min)   V(max)
0s        718.2mV    613.2mV    828.9mV
503ps     717.9mV    613.2mV    821mV
599ps     720.1mV    612.9mV    581.1mV
655ps     705.9mV    612.7mV    303.7mV
746ps     540.3mV    615.2mV    51.45mV
878ps     117mV      545mV      7.307mV
997ps     18.53mV    304.2mV    1.478mV
1.152ns   2.576mV    42.09mV    264.8uV
1.575ns   85.87uV    578.4uV    17.63uV
50ns      812.9nV    1.971uV    416.3nV
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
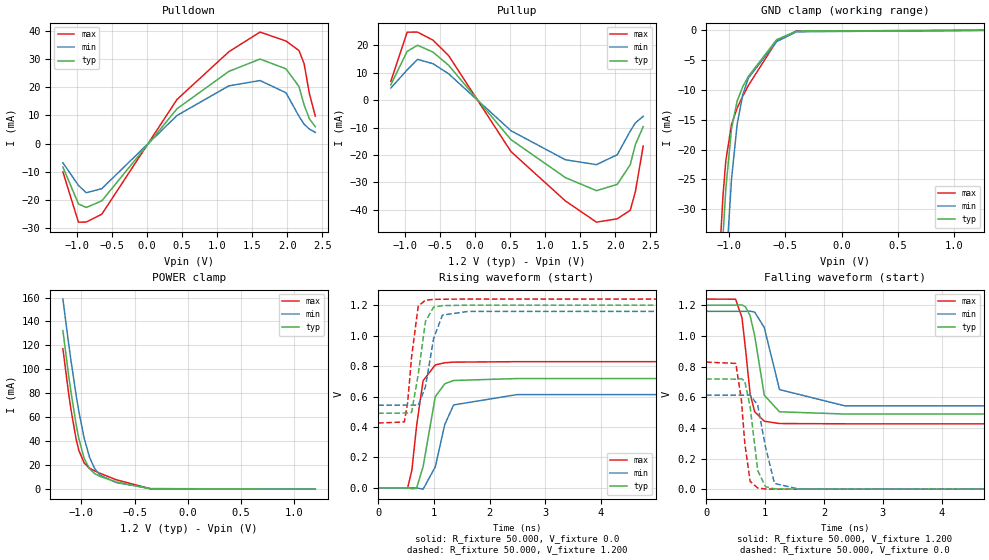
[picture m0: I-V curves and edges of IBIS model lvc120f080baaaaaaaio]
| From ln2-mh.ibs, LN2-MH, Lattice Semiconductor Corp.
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|   Model lvc120f080baaaaaaaio
[Model] lvc120f080baaaaaaaio
Model_type I/O
Polarity   Non-Inverting
Enable   Active-Low
Vinl =  0.420V
Vinh =  0.780V
Vmeas =  0.600V
Cref =  0.0F
Rref =  1.000M
Vref =  0.0V
C_comp   2.000pF   1.500pF   2.500pF
[Temperature Range]   25.000   0.125k   -40.000
[Voltage Range]   1.200V   1.160V   1.240V
[C Comp Corner]
C_comp   2.000pF   1.500pF   2.500pF
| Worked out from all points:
|   slope of the pulldown table from 0 to 0.18 V, typ, clamps not added: 31.6 ohm
|   slope of the pullup table from 0 to 0.18 V, typ, clamps not added: 31.8 ohm
|   GND clamp passes 1 mA (typ) near -0.54 V on its own axis
|   POWER clamp passes 1 mA (typ) near -0.43 V on its own axis
|   rising waveform, R_fixture 50.000, V_fixture 0.0: 20-80 % time 195ps typ, 250ps min, 156ps max; typ from 0 V to 0.718 V
|   rising waveform, R_fixture 50.000, V_fixture 1.200: 20-80 % time 148ps typ, 179ps min, 118ps max; typ from 0.49 V to 1.2 V
|   falling waveform, R_fixture 50.000, V_fixture 1.200: 20-80 % time 172ps typ, 226ps min, 136ps max; typ from 1.2 V to 0.49 V
|   falling waveform, R_fixture 50.000, V_fixture 0.0: 20-80 % time 134ps typ, 164ps min, 112ps max; typ from 0.718 V to 0 V
[Pulldown]
|Voltage   I(typ)   I(min)   I(max)
-1.2V     -8.322mA   -6.793mA   -10.02mA
-978mV    -21.36mA   -14.8mA    -27.82mA
-867mV    -22.61mA   -17.4mA    -27.76mA
-645mV    -20.27mA   -15.95mA   -24.99mA
428mV     12.34mA    9.951mA    15.63mA
1.168V    25.56mA    20.44mA    32.52mA
1.612V    29.91mA    22.31mA    39.46mA
1.982V    26.46mA    17.99mA    36.3mA
2.167V    20.2mA     9.683mA    32.94mA
2.241V    13.63mA    6.87mA     28.23mA
2.315V    8.812mA    5.151mA    17.76mA
2.4V      5.961mA    3.959mA    9.707mA
[Pullup]
|Voltage   I(typ)   I(min)   I(max)
-1.2V     5.592mA    4.415mA    6.856mA
-967mV    17.79mA    11.03mA    24.81mA
-819mV    20.03mA    14.89mA    24.83mA
-597mV    17.5mA     13.29mA    21.86mA
-375mV    12.71mA    9.614mA    16.24mA
513mV     -14.38mA   -11.14mA   -18.74mA
1.29V     -28.26mA   -21.75mA   -36.77mA
1.734V    -33.02mA   -23.52mA   -44.52mA
2.03V     -30.72mA   -19.9mA    -43.27mA
2.215V    -23.54mA   -11.27mA   -40.19mA
2.289V    -16.13mA   -8.294mA   -33.29mA
2.4V      -9.656mA   -5.88mA    -16.7mA
[GND_clamp]
|Voltage   I(typ)   I(min)   I(max)
-1.2V     -115.8mA   -133.1mA   -106.7mA
-1.1V     -56.13mA   -73.79mA   -46.76mA
-1.075V   -44.35mA   -61.25mA   -35.93mA
-1.05V    -34.4mA    -49.96mA   -27.58mA
-1.025V   -26.48mA   -40.08mA   -21.8mA
-975mV    -16.5mA    -24.97mA   -15.79mA
-925mV    -11.85mA   -15.76mA   -13.02mA
-875mV    -9.422mA   -10.76mA   -11.03mA
-825mV    -7.705mA   -7.983mA   -9.226mA
-575mV    -1.568mA   -1.879mA   -1.797mA
-400mV    -127.7uA   -246.9uA   -111uA
1.26V     0A         0A         0A
[POWER_clamp]
|Voltage   I(typ)   I(min)   I(max)
-1.175V   132.4mA    158.7mA    117.3mA
-1.125V   97.68mA    124.2mA    82.53mA
-1.1V     81.71mA    108mA      66.96mA
-1.05V    53.72mA    78.17mA    41.46mA
-1.025V   42.29mA    64.94mA    32.4mA
-975mV    25.73mA    42.64mA    21.9mA
-925mV    17mA       26.75mA    17.58mA
-875mV    12.91mA    17.01mA    15.19mA
-825mV    10.65mA    11.68mA    13.24mA
-675mV    6.1mA      5.538mA    7.913mA
-350mV    294.7uA    490.5uA    329uA
1.2V      0A         0A         0A
[Ramp]
| variable   typ   min   max
dV/dt_r   0.431/0.196n   0.368/0.251n   0.497/0.156n
dV/dt_f   0.426/0.173n   0.370/0.227n   0.488/0.136n
R_load = 50.000
[Rising Waveform]
R_fixture= 50.000
V_fixture= 0.0
V_fixture_min= 0.0
V_fixture_max= 0.0
|time   V(typ)   V(min)   V(max)
0s        21.16nV    961.3nV    2.149nV
527ps     246.8uV    -22.99uV   -2.504mV
605ps     -5.394mV   58.83uV    117.2mV
688ps     -2.912mV   119.5uV    404.7mV
806ps     139.4mV    -8.09mV    703.9mV
1.025ns   599.4mV    138.5mV    807.7mV
1.195ns   683.8mV    416.3mV    821.9mV
1.354ns   705.4mV    544.9mV    826mV
2.492ns   718.1mV    612.8mV    828.9mV
50ns      718.2mV    613.2mV    828.9mV
[Rising Waveform]
R_fixture= 50.000
V_fixture= 1.200
V_fixture_min= 1.160
V_fixture_max= 1.240
|time   V(typ)   V(min)   V(max)
0s        490.1mV    543mV      426.3mV
469ps     491.4mV    543.8mV    433mV
529ps     491.3mV    544mV      560.9mV
600ps     496.1mV    544.2mV    862.4mV
719ps     746.7mV    542.6mV    1.194V
849ps     1.094V     665mV      1.232V
995ps     1.187V     981.1mV    1.238V
1.154ns   1.197V     1.135V     1.239V
1.618ns   1.2V       1.159V     1.24V
50ns      1.2V       1.16V      1.24V
[Falling Waveform]
R_fixture= 50.000
V_fixture= 1.200
V_fixture_min= 1.160
V_fixture_max= 1.240
|time   V(typ)   V(min)   V(max)
0s        1.2V       1.16V      1.24V
500ps     1.2V       1.16V      1.239V
608ps     1.202V     1.16V      1.119V
668ps     1.189V     1.16V      915.7mV
746ps     1.132V     1.161V     623.4mV
824ps     1.001V     1.155V     504.9mV
987ps     612.8mV    1.054V     443.3mV
1.245ns   504.6mV    649.7mV    428.1mV
2.355ns   490.1mV    543.4mV    426.2mV
50ns      490mV      543mV      426.2mV
[Falling Waveform]
R_fixture= 50.000
V_fixture= 0.0
V_fixture_min= 0.0
V_fixture_max= 0.0
|time   V(typ)   V(min)   V(max)
0s        718.2mV    613.2mV    828.9mV
504ps     717.9mV    613.2mV    820.1mV
599ps     720.1mV    612.9mV    581.1mV
655ps     705.8mV    612.7mV    303.7mV
746ps     540mV      615.2mV    51.46mV
876ps     120.9mV    547.4mV    7.512mV
1.008ns   15.88mV    273.8mV    1.292mV
1.16ns    2.336mV    37.56mV    245.4uV
1.575ns   85.82uV    577.4uV    17.62uV
50ns      835.6nV    1.934uV    401.6nV
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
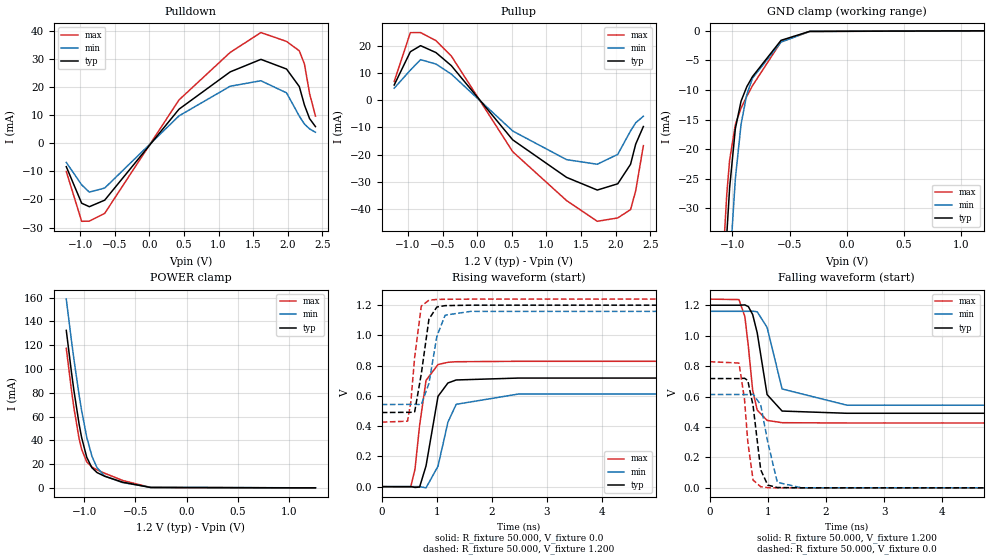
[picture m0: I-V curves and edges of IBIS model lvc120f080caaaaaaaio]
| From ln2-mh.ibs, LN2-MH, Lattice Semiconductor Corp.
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|   Model lvc120f080caaaaaaaio
[Model] lvc120f080caaaaaaaio
Model_type I/O
Polarity   Non-Inverting
Enable   Active-Low
Vinl =  0.420V
Vinh =  0.780V
Vmeas =  0.600V
Cref =  0.0F
Rref =  1.000M
Vref =  0.0V
C_comp   2.000pF   1.500pF   2.500pF
[Temperature Range]   25.000   0.125k   -40.000
[Voltage Range]   1.200V   1.160V   1.240V
[C Comp Corner]
C_comp   2.000pF   1.500pF   2.500pF
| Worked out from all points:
|   slope of the pulldown table from 0 to 0.18 V, typ, clamps not added: 31.9 ohm
|   slope of the pullup table from 0 to 0.18 V, typ, clamps not added: 31.6 ohm
|   GND clamp passes 1 mA (typ) near -0.53 V on its own axis
|   POWER clamp passes 1 mA (typ) near -0.43 V on its own axis
|   rising waveform, R_fixture 50.000, V_fixture 0.0: 20-80 % time 195ps typ, 251ps min, 156ps max; typ from 0 V to 0.718 V
|   rising waveform, R_fixture 50.000, V_fixture 1.200: 20-80 % time 148ps typ, 179ps min, 118ps max; typ from 0.49 V to 1.2 V
|   falling waveform, R_fixture 50.000, V_fixture 1.200: 20-80 % time 172ps typ, 226ps min, 136ps max; typ from 1.2 V to 0.49 V
|   falling waveform, R_fixture 50.000, V_fixture 0.0: 20-80 % time 134ps typ, 164ps min, 112ps max; typ from 0.718 V to 0 V
[Pulldown]
|Voltage   I(typ)   I(min)   I(max)
-1.2V     -8.31mA    -6.783mA   -10.01mA
-978mV    -21.32mA   -14.78mA   -27.77mA
-867mV    -22.57mA   -17.37mA   -27.71mA
-645mV    -20.24mA   -15.92mA   -24.94mA
428mV     12.17mA    9.784mA    15.46mA
1.168V    25.47mA    20.36mA    32.41mA
1.612V    29.93mA    22.31mA    39.48mA
1.982V    26.49mA    18mA       36.33mA
2.167V    20.22mA    9.693mA    32.97mA
2.241V    13.64mA    6.877mA    28.25mA
2.315V    8.821mA    5.157mA    17.77mA
2.4V      5.967mA    3.963mA    9.716mA
[Pullup]
|Voltage   I(typ)   I(min)   I(max)
-1.2V     5.598mA    4.42mA     6.864mA
-967mV    17.81mA    11.04mA    24.84mA
-819mV    20.05mA    14.91mA    24.86mA
-597mV    17.52mA    13.31mA    21.9mA
-375mV    12.72mA    9.609mA    16.26mA
513mV     -14.56mA   -11.31mA   -18.92mA
1.29V     -28.32mA   -21.81mA   -36.84mA
1.734V    -32.98mA   -23.5mA    -44.46mA
2.03V     -30.68mA   -19.88mA   -43.22mA
2.215V    -23.51mA   -11.26mA   -40.15mA
2.289V    -16.11mA   -8.282mA   -33.26mA
2.4V      -9.643mA   -5.87mA    -16.68mA
[GND_clamp]
|Voltage   I(typ)   I(min)   I(max)
-1.2V     -115.8mA   -133.1mA   -106.7mA
-1.1V     -56.15mA   -73.8mA    -46.79mA
-1.075V   -44.37mA   -61.27mA   -35.96mA
-1.05V    -34.42mA   -49.98mA   -27.62mA
-1.025V   -26.5mA    -40.1mA    -21.84mA
-975mV    -16.54mA   -25mA      -15.84mA
-925mV    -11.89mA   -15.79mA   -13.07mA
-875mV    -9.459mA   -10.78mA   -11.08mA
-825mV    -7.743mA   -8.01mA    -9.276mA
-575mV    -1.608mA   -1.904mA   -1.854mA
-325mV    -94.59uA   -107.1uA   -110.5uA
1.2V      0A         0A         0A
[POWER_clamp]
|Voltage   I(typ)   I(min)   I(max)
-1.175V   132.4mA    158.7mA    117.3mA
-1.125V   97.67mA    124.2mA    82.52mA
-1.1V     81.7mA     108mA      66.95mA
-1.05V    53.71mA    78.17mA    41.44mA
-1.025V   42.27mA    64.93mA    32.38mA
-975mV    25.71mA    42.63mA    21.87mA
-925mV    16.98mA    26.74mA    17.54mA
-875mV    12.89mA    17mA       15.15mA
-800mV    9.742mA    10mA       12.28mA
-625mV    4.793mA    4.396mA    6.256mA
-350mV    291.9uA    500.3uA    309.5uA
1.26V     0A         0A         0A
[Ramp]
| variable   typ   min   max
dV/dt_r   0.431/0.196n   0.368/0.251n   0.497/0.157n
dV/dt_f   0.426/0.173n   0.370/0.227n   0.488/0.136n
R_load = 50.000
[Rising Waveform]
R_fixture= 50.000
V_fixture= 0.0
V_fixture_min= 0.0
V_fixture_max= 0.0
|time   V(typ)   V(min)   V(max)
0s        21.16nV    961.3nV    2.149nV
527ps     246.8uV    -22.85uV   -2.504mV
605ps     -5.394mV   58.68uV    117.2mV
688ps     -2.912mV   115.8uV    404.7mV
805ps     137.3mV    -8.071mV   702.6mV
1.023ns   597.3mV    135.3mV    807.4mV
1.203ns   685.5mV    426.3mV    822.2mV
1.353ns   705.4mV    544.4mV    826mV
2.491ns   718.1mV    612.8mV    828.9mV
50ns      718.2mV    613.2mV    828.9mV
[Rising Waveform]
R_fixture= 50.000
V_fixture= 1.200
V_fixture_min= 1.160
V_fixture_max= 1.240
|time   V(typ)   V(min)   V(max)
0s        490.1mV    543mV      426.3mV
469ps     491.4mV    543.8mV    433mV
529ps     491.4mV    544mV      560.9mV
599ps     495.5mV    544.2mV    858mV
719ps     745.9mV    542.6mV    1.194V
858ps     1.108V     683mV      1.233V
1.002ns   1.188V     993.9mV    1.238V
1.152ns   1.197V     1.134V     1.239V
1.618ns   1.2V       1.159V     1.24V
50ns      1.2V       1.16V      1.24V
[Falling Waveform]
R_fixture= 50.000
V_fixture= 1.200
V_fixture_min= 1.160
V_fixture_max= 1.240
|time   V(typ)   V(min)   V(max)
0s        1.2V       1.16V      1.24V
504ps     1.2V       1.16V      1.237V
605ps     1.202V     1.16V      1.125V
665ps     1.191V     1.16V      929.1mV
739ps     1.139V     1.161V     641.7mV
817ps     1.019V     1.157V     511mV
987ps     612.8mV    1.054V     443.3mV
1.245ns   504.6mV    649.7mV    428.1mV
2.355ns   490.1mV    543.4mV    426.2mV
50ns      490mV      543mV      426.2mV
[Falling Waveform]
R_fixture= 50.000
V_fixture= 0.0
V_fixture_min= 0.0
V_fixture_max= 0.0
|time   V(typ)   V(min)   V(max)
0s        718.2mV    613.2mV    828.9mV
504ps     717.9mV    613.2mV    820.1mV
599ps     720.1mV    612.9mV    581.1mV
655ps     705.9mV    612.7mV    303.7mV
746ps     540.3mV    615.2mV    51.45mV
877ps     119.1mV    546.4mV    7.418mV
998ps     18.26mV    301.5mV    1.46mV
1.163ns   2.256mV    36.24mV    238.5uV
1.576ns   85.45uV    574.7uV    17.57uV
50ns      812.9nV    1.931uV    419.7nV
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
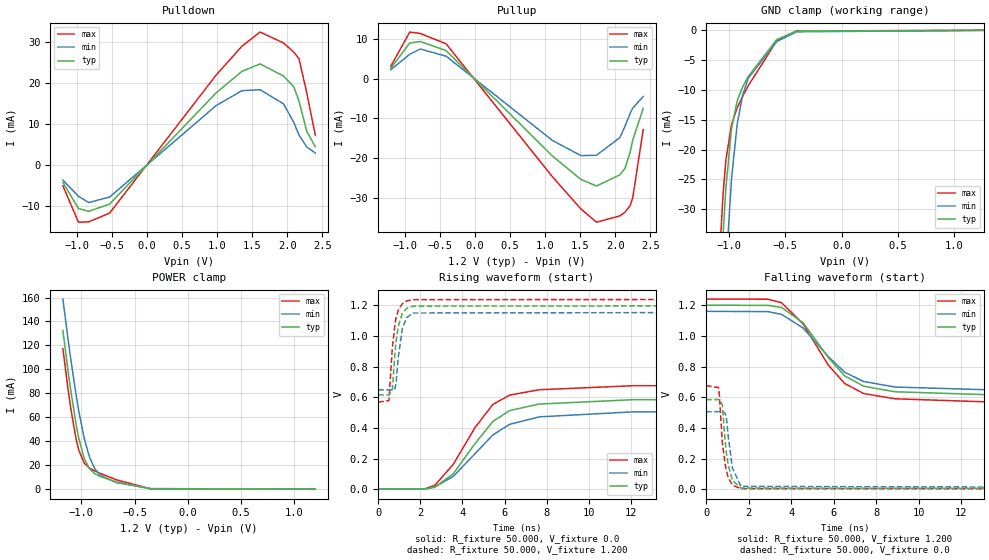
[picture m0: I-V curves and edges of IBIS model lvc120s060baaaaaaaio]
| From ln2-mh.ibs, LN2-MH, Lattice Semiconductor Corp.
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|   Model lvc120s060baaaaaaaio
[Model] lvc120s060baaaaaaaio
Model_type I/O
Polarity   Non-Inverting
Enable   Active-Low
Vinl =  0.420V
Vinh =  0.780V
Vmeas =  0.600V
Cref =  0.0F
Rref =  1.000M
Vref =  0.0V
C_comp   2.000pF   1.500pF   2.500pF
[Temperature Range]   25.000   0.125k   -40.000
[Voltage Range]   1.200V   1.160V   1.240V
[C Comp Corner]
C_comp   2.000pF   1.500pF   2.500pF
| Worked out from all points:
|   slope of the pulldown table from 0 to 0.18 V, typ, clamps not added: 53.5 ohm
|   slope of the pullup table from 0 to 0.18 V, typ, clamps not added: 54.5 ohm
|   GND clamp passes 1 mA (typ) near -0.54 V on its own axis
|   POWER clamp passes 1 mA (typ) near -0.43 V on its own axis
|   rising waveform, R_fixture 50.000, V_fixture 0.0: 20-80 % time 1.99ns typ, 2.24ns min, 1.91ns max; typ from 0 V to 0.584 V
|   rising waveform, R_fixture 50.000, V_fixture 1.200: 20-80 % time 267ps typ, 277ps min, 259ps max; typ from 0.615 V to 1.2 V
|   falling waveform, R_fixture 50.000, V_fixture 1.200: 20-80 % time 2.01ns typ, 2.15ns min, 1.99ns max; typ from 1.2 V to 0.615 V
|   falling waveform, R_fixture 50.000, V_fixture 0.0: 20-80 % time 288ps typ, 301ps min, 281ps max; typ from 0.584 V to 0 V
[Pulldown]
|Voltage   I(typ)   I(min)   I(max)
-1.2V     -4.215mA   -3.606mA   -5.005mA
-978mV    -10.54mA   -7.565mA   -13.86mA
-830mV    -11.21mA   -9.068mA   -13.76mA
-534mV    -9.444mA   -7.737mA   -11.65mA
983mV     17.59mA    14.51mA    21.91mA
1.353V    22.87mA    18.17mA    29mA
1.612V    24.69mA    18.4mA     32.44mA
1.945V    21.75mA    14.98mA    29.81mA
2.093V    19.13mA    10.46mA    27.56mA
2.167V    15.67mA    7.395mA    25.98mA
2.278V    8.261mA    4.461mA    17.68mA
2.4V      4.525mA    2.971mA    7.343mA
[Pullup]
|Voltage   I(typ)   I(min)   I(max)
-1.2V     2.727mA    2.327mA    3.207mA
-930mV    9.072mA    6.215mA    11.83mA
-782mV    9.439mA    7.547mA    11.49mA
-412mV    7.165mA    5.748mA    8.874mA
1.105V    -19.5mA    -15.56mA   -24.74mA
1.512V    -25.42mA   -19.39mA   -32.88mA
1.734V    -27.07mA   -19.3mA    -36.22mA
2.067V    -24.26mA   -14.84mA   -34.62mA
2.141V    -22.58mA   -11.94mA   -33.68mA
2.215V    -18.42mA   -8.669mA   -31.99mA
2.252V    -15.35mA   -7.355mA   -29.89mA
2.4V      -7.451mA   -4.454mA   -12.83mA
[GND_clamp]
|Voltage   I(typ)   I(min)   I(max)
-1.2V     -115.8mA   -133.1mA   -106.7mA
-1.1V     -56.13mA   -73.79mA   -46.76mA
-1.075V   -44.35mA   -61.25mA   -35.93mA
-1.05V    -34.4mA    -49.96mA   -27.58mA
-1.025V   -26.48mA   -40.08mA   -21.8mA
-975mV    -16.5mA    -24.97mA   -15.79mA
-925mV    -11.85mA   -15.76mA   -13.02mA
-875mV    -9.422mA   -10.76mA   -11.03mA
-825mV    -7.705mA   -7.983mA   -9.226mA
-575mV    -1.568mA   -1.879mA   -1.797mA
-400mV    -127.7uA   -246.9uA   -111uA
1.26V     0A         0A         0A
[POWER_clamp]
|Voltage   I(typ)   I(min)   I(max)
-1.175V   132.4mA    158.7mA    117.3mA
-1.125V   97.68mA    124.2mA    82.53mA
-1.1V     81.71mA    108mA      66.96mA
-1.05V    53.72mA    78.17mA    41.46mA
-1.025V   42.29mA    64.94mA    32.4mA
-975mV    25.73mA    42.64mA    21.9mA
-925mV    17mA       26.75mA    17.58mA
-875mV    12.91mA    17.01mA    15.19mA
-825mV    10.65mA    11.68mA    13.24mA
-675mV    6.1mA      5.538mA    7.913mA
-350mV    294.7uA    490.5uA    329uA
1.2V      0A         0A         0A
[Ramp]
| variable   typ   min   max
dV/dt_r   0.351/2.008n   0.303/2.247n   0.405/1.912n
dV/dt_f   0.351/2.014n   0.308/2.171n   0.403/2.007n
R_load = 50.000
[Rising Waveform]
R_fixture= 50.000
V_fixture= 0.0
V_fixture_min= 0.0
V_fixture_max= 0.0
|time   V(typ)   V(min)   V(max)
0s        29.47nV    1.263uV    3.133nV
2.2ns     611.7uV    1.138mV    1.56mV
2.695ns   12.73mV    14.79mV    25.85mV
3.567ns   101.2mV    83.49mV    162.4mV
4.6ns     297.5mV    231.7mV    402.2mV
5.44ns    441.2mV    352.9mV    552.1mV
6.24ns    512.7mV    423.2mV    613.4mV
7.645ns   555.1mV    471.6mV    648.5mV
12.07ns   583.5mV    504.1mV    674.6mV
50ns      584.3mV    505.1mV    675.7mV
[Rising Waveform]
R_fixture= 50.000
V_fixture= 1.200
V_fixture_min= 1.160
V_fixture_max= 1.240
|time   V(typ)   V(min)   V(max)
0s        614.9mV    647mV      567.8mV
510ps     615.2mV    647.1mV    577.8mV
667ps     641.2mV    647.3mV    913mV
798ps     890.6mV    655.3mV    1.078V
848ps     960.5mV    692.1mV    1.116V
948ps     1.06V      854.4mV    1.166V
1.149ns   1.149V     1.05V      1.211V
1.354ns   1.18V      1.119V     1.228V
1.648ns   1.194V     1.149V     1.236V
50ns      1.2V       1.16V      1.24V
[Falling Waveform]
R_fixture= 50.000
V_fixture= 1.200
V_fixture_min= 1.160
V_fixture_max= 1.240
|time   V(typ)   V(min)   V(max)
0s        1.2V       1.16V      1.24V
2.901ns   1.199V     1.158V     1.239V
3.551ns   1.185V     1.14V      1.216V
4.563ns   1.085V     1.051V     1.077V
5.743ns   858.9mV    865.4mV    809.7mV
6.514ns   739.3mV    762.9mV    689.4mV
7.403ns   671.8mV    702.3mV    624mV
8.883ns   635.2mV    666.1mV    589.4mV
13.45ns   615.2mV    647.4mV    568.2mV
50ns      614.9mV    646.9mV    567.8mV
[Falling Waveform]
R_fixture= 50.000
V_fixture= 0.0
V_fixture_min= 0.0
V_fixture_max= 0.0
|time   V(typ)   V(min)   V(max)
0s        584.3mV    505.1mV    675.7mV
580ps     584.5mV    505.1mV    663mV
620ps     584.5mV    505mV      620.3mV
763ps     552.2mV    505.2mV    302.9mV
893ps     315.8mV    496.7mV    164.4mV
962ps     228.3mV    456.4mV    116.6mV
1.042ns   156.9mV    341.6mV    75.3mV
1.234ns   57.47mV    140.8mV    25.98mV
1.632ns   7.142mV    18.32mV    3.484mV
50ns      1.32uV     2.627uV    874.6nV
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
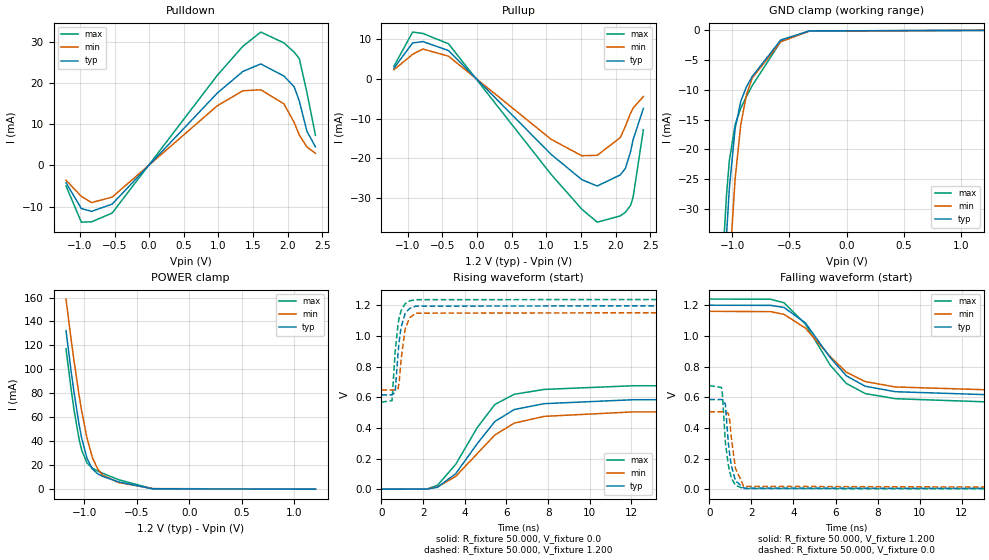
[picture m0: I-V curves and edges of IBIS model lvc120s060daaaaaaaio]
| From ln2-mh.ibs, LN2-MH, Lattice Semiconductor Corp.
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|   Model lvc120s060daaaaaaaio
[Model] lvc120s060daaaaaaaio
Model_type I/O
Polarity   Non-Inverting
Enable   Active-Low
Vinl =  0.420V
Vinh =  0.780V
Vmeas =  0.600V
Cref =  0.0F
Rref =  1.000M
Vref =  0.0V
C_comp   2.000pF   1.500pF   2.500pF
[Temperature Range]   25.000   0.125k   -40.000
[Voltage Range]   1.200V   1.160V   1.240V
[C Comp Corner]
C_comp   2.000pF   1.500pF   2.500pF
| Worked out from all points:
|   slope of the pulldown table from 0 to 0.18 V, typ, clamps not added: 54.3 ohm
|   slope of the pullup table from 0 to 0.18 V, typ, clamps not added: 54.5 ohm
|   GND clamp passes 1 mA (typ) near -0.53 V on its own axis
|   POWER clamp passes 1 mA (typ) near -0.43 V on its own axis
|   rising waveform, R_fixture 50.000, V_fixture 0.0: 20-80 % time 1.99ns typ, 2.24ns min, 1.91ns max; typ from 0 V to 0.584 V
|   rising waveform, R_fixture 50.000, V_fixture 1.200: 20-80 % time 267ps typ, 278ps min, 259ps max; typ from 0.615 V to 1.2 V
|   falling waveform, R_fixture 50.000, V_fixture 1.200: 20-80 % time 2.01ns typ, 2.15ns min, 1.99ns max; typ from 1.2 V to 0.615 V
|   falling waveform, R_fixture 50.000, V_fixture 0.0: 20-80 % time 287ps typ, 301ps min, 281ps max; typ from 0.584 V to 0 V
[Pulldown]
|Voltage   I(typ)   I(min)   I(max)
-1.2V     -4.202mA   -3.596mA   -4.99mA
-978mV    -10.5mA    -7.543mA   -13.81mA
-830mV    -11.17mA   -9.041mA   -13.71mA
-534mV    -9.404mA   -7.714mA   -11.59mA
983mV     17.59mA    14.51mA    21.91mA
1.353V    22.87mA    18.17mA    29mA
1.612V    24.69mA    18.4mA     32.44mA
1.945V    21.75mA    14.98mA    29.81mA
2.093V    19.13mA    10.46mA    27.56mA
2.167V    15.67mA    7.395mA    25.98mA
2.278V    8.261mA    4.461mA    17.68mA
2.4V      4.525mA    2.971mA    7.343mA
[Pullup]
|Voltage   I(typ)   I(min)   I(max)
-1.2V     2.727mA    2.327mA    3.207mA
-930mV    9.072mA    6.215mA    11.83mA
-782mV    9.439mA    7.547mA    11.49mA
-412mV    7.165mA    5.748mA    8.874mA
1.068V    -19.03mA   -15.23mA   -24.09mA
1.512V    -25.42mA   -19.39mA   -32.87mA
1.734V    -27.03mA   -19.28mA   -36.16mA
2.067V    -24.22mA   -14.81mA   -34.57mA
2.141V    -22.55mA   -11.92mA   -33.64mA
2.215V    -18.4mA    -8.652mA   -31.94mA
2.252V    -15.33mA   -7.341mA   -29.85mA
2.4V      -7.439mA   -4.445mA   -12.81mA
[GND_clamp]
|Voltage   I(typ)   I(min)   I(max)
-1.2V     -115.8mA   -133.1mA   -106.7mA
-1.1V     -56.15mA   -73.8mA    -46.79mA
-1.075V   -44.37mA   -61.27mA   -35.96mA
-1.05V    -34.42mA   -49.98mA   -27.62mA
-1.025V   -26.5mA    -40.1mA    -21.84mA
-975mV    -16.54mA   -25mA      -15.84mA
-925mV    -11.89mA   -15.79mA   -13.07mA
-875mV    -9.459mA   -10.78mA   -11.08mA
-825mV    -7.743mA   -8.01mA    -9.276mA
-575mV    -1.608mA   -1.904mA   -1.854mA
-325mV    -94.59uA   -107.1uA   -110.5uA
1.2V      -90.03nA   2.134uA    -12.11uA
[POWER_clamp]
|Voltage   I(typ)   I(min)   I(max)
-1.175V   132.4mA    158.7mA    117.3mA
-1.125V   97.68mA    124.2mA    82.53mA
-1.1V     81.71mA    108mA      66.96mA
-1.05V    53.72mA    78.17mA    41.46mA
-1.025V   42.29mA    64.94mA    32.4mA
-975mV    25.73mA    42.64mA    21.9mA
-925mV    17mA       26.75mA    17.58mA
-875mV    12.91mA    17.01mA    15.19mA
-825mV    10.65mA    11.68mA    13.24mA
-675mV    6.1mA      5.538mA    7.913mA
-350mV    294.7uA    490.5uA    329uA
1.2V      0A         0A         12.42uA
[Ramp]
| variable   typ   min   max
dV/dt_r   0.351/2.007n   0.303/2.249n   0.405/1.911n
dV/dt_f   0.351/2.023n   0.308/2.159n   0.403/2.006n
R_load = 50.000
[Rising Waveform]
R_fixture= 50.000
V_fixture= 0.0
V_fixture_min= 0.0
V_fixture_max= 0.0
|time   V(typ)   V(min)   V(max)
0s        29.47nV    1.263uV    3.133nV
2.199ns   609.1uV    1.131mV    1.548mV
2.69ns    12.47mV    14.59mV    25.43mV
3.563ns   100.6mV    83.12mV    161.6mV
4.599ns   297.2mV    231.8mV    402mV
5.442ns   441.4mV    353.4mV    552.3mV
6.37ns    519.2mV    430.5mV    618.9mV
7.81ns    557.7mV    474.9mV    650.7mV
12.09ns   583.5mV    504.1mV    674.6mV
50ns      584.3mV    505.1mV    675.7mV
[Rising Waveform]
R_fixture= 50.000
V_fixture= 1.200
V_fixture_min= 1.160
V_fixture_max= 1.240
|time   V(typ)   V(min)   V(max)
0s        614.9mV    647mV      567.8mV
510ps     615.2mV    647.1mV    577.8mV
658ps     632.7mV    647.3mV    897.5mV
798ps     890.4mV    655.4mV    1.078V
854ps     967.8mV    700.2mV    1.12V
944ps     1.057V     848.6mV    1.164V
1.139ns   1.146V     1.045V     1.21V
1.348ns   1.179V     1.118V     1.228V
1.646ns   1.194V     1.148V     1.236V
50ns      1.2V       1.16V      1.24V
[Falling Waveform]
R_fixture= 50.000
V_fixture= 1.200
V_fixture_min= 1.160
V_fixture_max= 1.240
|time   V(typ)   V(min)   V(max)
0s        1.2V       1.16V      1.24V
2.902ns   1.199V     1.158V     1.239V
3.55ns    1.185V     1.14V      1.216V
4.563ns   1.085V     1.051V     1.077V
5.743ns   858.9mV    865.2mV    809.8mV
6.513ns   739.5mV    762.8mV    689.6mV
7.412ns   671.4mV    701.8mV    623.6mV
8.842ns   635.7mV    666.6mV    590mV
13.42ns   615.3mV    647.4mV    568.2mV
50ns      614.9mV    646.9mV    567.8mV
[Falling Waveform]
R_fixture= 50.000
V_fixture= 0.0
V_fixture_min= 0.0
V_fixture_max= 0.0
|time   V(typ)   V(min)   V(max)
0s        584.3mV    505.1mV    675.7mV
580ps     584.5mV    505.1mV    663mV
619ps     584.5mV    505mV      622mV
760ps     555mV      505.2mV    307.3mV
901ps     303.9mV    494.3mV    158.3mV
971ps     218.9mV    446.4mV    111.1mV
1.051ns   150.3mV    328.4mV    71.65mV
1.241ns   55.32mV    136.2mV    25mV
1.631ns   7.176mV    18.42mV    3.499mV
50ns      1.323uV    2.629uV    871.8nV
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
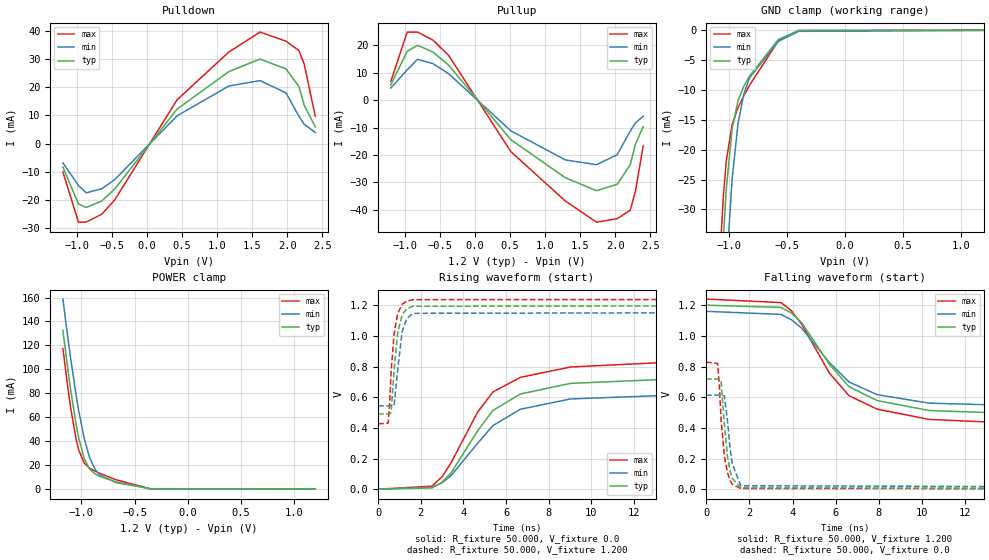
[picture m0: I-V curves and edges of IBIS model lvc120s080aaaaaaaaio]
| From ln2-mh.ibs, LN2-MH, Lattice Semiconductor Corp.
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|   Model lvc120s080aaaaaaaaio
[Model] lvc120s080aaaaaaaaio
Model_type I/O
Polarity   Non-Inverting
Enable   Active-Low
Vinl =  0.420V
Vinh =  0.780V
Vmeas =  0.600V
Cref =  0.0F
Rref =  1.000M
Vref =  0.0V
C_comp   2.000pF   1.500pF   2.500pF
[Temperature Range]   25.000   0.125k   -40.000
[Voltage Range]   1.200V   1.160V   1.240V
[C Comp Corner]
C_comp   2.000pF   1.500pF   2.500pF
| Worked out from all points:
|   slope of the pulldown table from 0 to 0.18 V, typ, clamps not added: 31.6 ohm
|   slope of the pullup table from 0 to 0.18 V, typ, clamps not added: 31.6 ohm
|   GND clamp passes 1 mA (typ) near -0.54 V on its own axis
|   POWER clamp passes 1 mA (typ) near -0.43 V on its own axis
|   rising waveform, R_fixture 50.000, V_fixture 0.0: 20-80 % time 2.33ns typ, 2.49ns min, 2.26ns max; typ from 0 V to 0.718 V
|   rising waveform, R_fixture 50.000, V_fixture 1.200: 20-80 % time 270ps typ, 284ps min, 261ps max; typ from 0.49 V to 1.2 V
|   falling waveform, R_fixture 50.000, V_fixture 1.200: 20-80 % time 2.41ns typ, 2.48ns min, 2.41ns max; typ from 1.2 V to 0.49 V
|   falling waveform, R_fixture 50.000, V_fixture 0.0: 20-80 % time 296ps typ, 313ps min, 284ps max; typ from 0.718 V to 0 V
[Pulldown]
|Voltage   I(typ)   I(min)   I(max)
-1.2V     -8.325mA   -6.797mA   -10.02mA
-978mV    -21.37mA   -14.81mA   -27.83mA
-867mV    -22.62mA   -17.41mA   -27.77mA
-645mV    -20.31mA   -15.98mA   -25.02mA
-460mV    -16.04mA   -12.72mA   -19.91mA
428mV     12.25mA    9.863mA    15.54mA
1.168V    25.56mA    20.45mA    32.5mA
1.612V    29.98mA    22.35mA    39.55mA
1.982V    26.5mA     18.02mA    36.34mA
2.167V    20.23mA    9.701mA    32.98mA
2.241V    13.65mA    6.883mA    28.26mA
2.4V      5.97mA     3.966mA    9.719mA
[Pullup]
|Voltage   I(typ)   I(min)   I(max)
-1.2V     5.601mA    4.423mA    6.866mA
-967mV    17.82mA    11.05mA    24.85mA
-819mV    20.07mA    14.93mA    24.87mA
-597mV    17.54mA    13.33mA    21.92mA
-375mV    12.79mA    9.668mA    16.33mA
513mV     -14.47mA   -11.22mA   -18.83mA
1.29V     -28.35mA   -21.84mA   -36.86mA
1.734V    -33.07mA   -23.56mA   -44.58mA
2.03V     -30.73mA   -19.92mA   -43.29mA
2.215V    -23.55mA   -11.28mA   -40.2mA
2.289V    -16.13mA   -8.3mA     -33.3mA
2.4V      -9.659mA   -5.883mA   -16.7mA
[GND_clamp]
|Voltage   I(typ)   I(min)   I(max)
-1.2V     -115.8mA   -133.1mA   -106.7mA
-1.1V     -56.13mA   -73.78mA   -46.76mA
-1.075V   -44.35mA   -61.25mA   -35.92mA
-1.05V    -34.39mA   -49.96mA   -27.58mA
-1.025V   -26.47mA   -40.07mA   -21.79mA
-975mV    -16.49mA   -24.96mA   -15.78mA
-925mV    -11.84mA   -15.75mA   -13.01mA
-875mV    -9.407mA   -10.74mA   -11.02mA
-825mV    -7.688mA   -7.964mA   -9.21mA
-575mV    -1.526mA   -1.839mA   -1.756mA
-400mV    -41.92uA   -170.5uA   -22.66uA
1.2V      2.678pA    5.169nA    0A
[POWER_clamp]
|Voltage   I(typ)   I(min)   I(max)
-1.175V   132.4mA    158.7mA    117.3mA
-1.125V   97.66mA    124.2mA    82.52mA
-1.1V     81.7mA     108mA      66.94mA
-1.05V    53.7mA     78.16mA    41.43mA
-1.025V   42.27mA    64.92mA    32.37mA
-975mV    25.7mA     42.62mA    21.86mA
-925mV    16.96mA    26.72mA    17.53mA
-875mV    12.88mA    16.98mA    15.14mA
-825mV    10.61mA    11.65mA    13.19mA
-675mV    6.055mA    5.5mA      7.862mA
-350mV    219.1uA    435.6uA    237.4uA
1.2V      0A         0A         0A
[Ramp]
| variable   typ   min   max
dV/dt_r   0.431/2.327n   0.368/2.494n   0.497/2.267n
dV/dt_f   0.426/2.408n   0.370/2.504n   0.488/2.411n
R_load = 50.000
[Rising Waveform]
R_fixture= 50.000
V_fixture= 0.0
V_fixture_min= 0.0
V_fixture_max= 0.0
|time   V(typ)   V(min)   V(max)
0s        21.16nV    961.3nV    2.149nV
2.523ns   8.479mV    11.22mV    19.49mV
2.996ns   45.16mV    41.8mV     80.53mV
3.414ns   104.7mV    87.07mV    171.1mV
4.66ns    378.9mV    297.9mV    501mV
5.38ns    513.1mV    414.2mV    633.5mV
6.673ns   620.6mV    521.2mV    729.3mV
9.017ns   689.9mV    588.5mV    796.6mV
13.67ns   717.8mV    612.7mV    828.4mV
50ns      718.3mV    613.2mV    828.9mV
[Rising Waveform]
R_fixture= 50.000
V_fixture= 1.200
V_fixture_min= 1.160
V_fixture_max= 1.240
|time   V(typ)   V(min)   V(max)
0s        490.1mV    543mV      426.3mV
467ps     491.1mV    543.7mV    431mV
536ps     490.9mV    543.9mV    558mV
609ps     502.7mV    544mV      772.7mV
749ps     779.7mV    547mV      1.014V
912ps     1.018V     774.4mV    1.145V
1.123ns   1.138V     1.026V     1.206V
1.333ns   1.176V     1.111V     1.226V
1.629ns   1.193V     1.147V     1.236V
50ns      1.2V       1.16V      1.24V
[Falling Waveform]
R_fixture= 50.000
V_fixture= 1.200
V_fixture_min= 1.160
V_fixture_max= 1.240
|time   V(typ)   V(min)   V(max)
0s        1.2V       1.16V      1.24V
3.464ns   1.186V     1.14V      1.217V
3.954ns   1.149V     1.105V     1.163V
4.427ns   1.085V     1.049V     1.075V
5.705ns   814.7mV    825.9mV    757.4mV
6.614ns   668.3mV    699.1mV    609.6mV
7.914ns   577.8mV    616.7mV    521.8mV
10.32ns   513.2mV    561mV      454.9mV
14.81ns   490.6mV    543.7mV    426.9mV
50ns      490mV      543mV      426.2mV
[Falling Waveform]
R_fixture= 50.000
V_fixture= 0.0
V_fixture_min= 0.0
V_fixture_max= 0.0
|time   V(typ)   V(min)   V(max)
0s        718.2mV    613.2mV    828.9mV
531ps     717.8mV    613.1mV    819.9mV
621ps     718.5mV    612.9mV    657mV
694ps     700.4mV    613mV      449.8mV
844ps     424.7mV    608.2mV    217.1mV
986ps     215.1mV    453.9mV    109.2mV
1.101ns   125mV      273.4mV    57.86mV
1.21ns    70.41mV    165.9mV    31.65mV
1.606ns   8.806mV    22.45mV    4.255mV
50ns      960.1nV    2.023uV    603.8nV
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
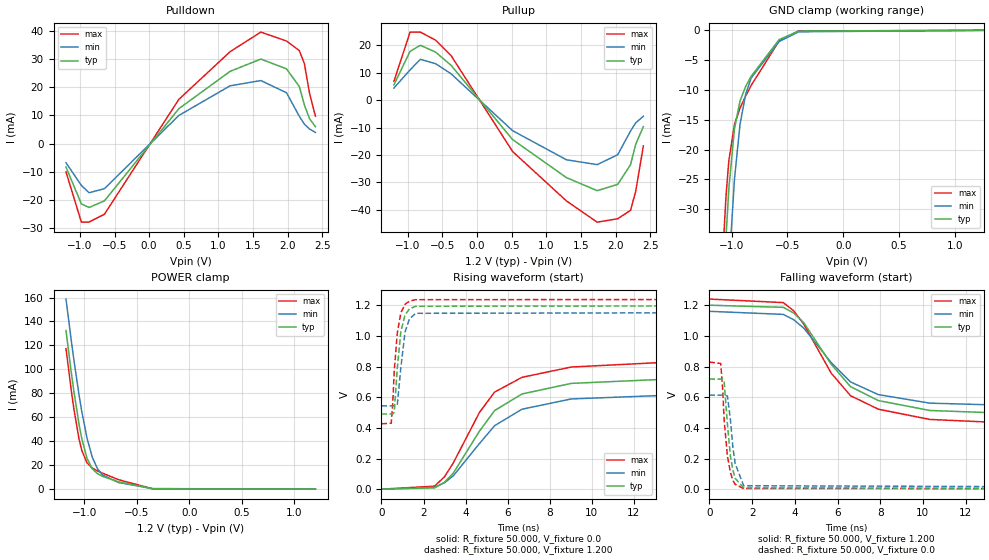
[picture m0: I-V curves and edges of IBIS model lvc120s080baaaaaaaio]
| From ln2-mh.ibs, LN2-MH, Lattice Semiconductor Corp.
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|   Model lvc120s080baaaaaaaio
[Model] lvc120s080baaaaaaaio
Model_type I/O
Polarity   Non-Inverting
Enable   Active-Low
Vinl =  0.420V
Vinh =  0.780V
Vmeas =  0.600V
Cref =  0.0F
Rref =  1.000M
Vref =  0.0V
C_comp   2.000pF   1.500pF   2.500pF
[Temperature Range]   25.000   0.125k   -40.000
[Voltage Range]   1.200V   1.160V   1.240V
[C Comp Corner]
C_comp   2.000pF   1.500pF   2.500pF
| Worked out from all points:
|   slope of the pulldown table from 0 to 0.18 V, typ, clamps not added: 31.6 ohm
|   slope of the pullup table from 0 to 0.18 V, typ, clamps not added: 31.8 ohm
|   GND clamp passes 1 mA (typ) near -0.54 V on its own axis
|   POWER clamp passes 1 mA (typ) near -0.43 V on its own axis
|   rising waveform, R_fixture 50.000, V_fixture 0.0: 20-80 % time 2.33ns typ, 2.49ns min, 2.26ns max; typ from 0 V to 0.718 V
|   rising waveform, R_fixture 50.000, V_fixture 1.200: 20-80 % time 270ps typ, 284ps min, 262ps max; typ from 0.49 V to 1.2 V
|   falling waveform, R_fixture 50.000, V_fixture 1.200: 20-80 % time 2.41ns typ, 2.48ns min, 2.4ns max; typ from 1.2 V to 0.49 V
|   falling waveform, R_fixture 50.000, V_fixture 0.0: 20-80 % time 296ps typ, 313ps min, 284ps max; typ from 0.718 V to 0 V
[Pulldown]
|Voltage   I(typ)   I(min)   I(max)
-1.2V     -8.322mA   -6.793mA   -10.02mA
-978mV    -21.36mA   -14.8mA    -27.82mA
-867mV    -22.61mA   -17.4mA    -27.76mA
-645mV    -20.27mA   -15.95mA   -24.99mA
428mV     12.34mA    9.951mA    15.63mA
1.168V    25.56mA    20.44mA    32.52mA
1.612V    29.91mA    22.31mA    39.46mA
1.982V    26.46mA    17.99mA    36.3mA
2.167V    20.2mA     9.683mA    32.94mA
2.241V    13.63mA    6.87mA     28.23mA
2.315V    8.812mA    5.151mA    17.76mA
2.4V      5.961mA    3.959mA    9.707mA
[Pullup]
|Voltage   I(typ)   I(min)   I(max)
-1.2V     5.592mA    4.415mA    6.856mA
-967mV    17.79mA    11.03mA    24.81mA
-819mV    20.03mA    14.89mA    24.83mA
-597mV    17.5mA     13.29mA    21.86mA
-375mV    12.71mA    9.614mA    16.24mA
513mV     -14.38mA   -11.14mA   -18.74mA
1.29V     -28.26mA   -21.75mA   -36.77mA
1.734V    -33.02mA   -23.52mA   -44.52mA
2.03V     -30.72mA   -19.9mA    -43.27mA
2.215V    -23.54mA   -11.27mA   -40.19mA
2.289V    -16.13mA   -8.294mA   -33.29mA
2.4V      -9.656mA   -5.88mA    -16.7mA
[GND_clamp]
|Voltage   I(typ)   I(min)   I(max)
-1.2V     -115.8mA   -133.1mA   -106.7mA
-1.1V     -56.13mA   -73.79mA   -46.76mA
-1.075V   -44.35mA   -61.25mA   -35.93mA
-1.05V    -34.4mA    -49.96mA   -27.58mA
-1.025V   -26.48mA   -40.08mA   -21.8mA
-975mV    -16.5mA    -24.97mA   -15.79mA
-925mV    -11.85mA   -15.76mA   -13.02mA
-875mV    -9.422mA   -10.76mA   -11.03mA
-825mV    -7.705mA   -7.983mA   -9.226mA
-575mV    -1.568mA   -1.879mA   -1.797mA
-400mV    -127.7uA   -246.9uA   -111uA
1.26V     0A         0A         0A
[POWER_clamp]
|Voltage   I(typ)   I(min)   I(max)
-1.175V   132.4mA    158.7mA    117.3mA
-1.125V   97.68mA    124.2mA    82.53mA
-1.1V     81.71mA    108mA      66.96mA
-1.05V    53.72mA    78.17mA    41.46mA
-1.025V   42.29mA    64.94mA    32.4mA
-975mV    25.73mA    42.64mA    21.9mA
-925mV    17mA       26.75mA    17.58mA
-875mV    12.91mA    17.01mA    15.19mA
-825mV    10.65mA    11.68mA    13.24mA
-675mV    6.1mA      5.538mA    7.913mA
-350mV    294.7uA    490.5uA    329uA
1.2V      0A         0A         0A
[Ramp]
| variable   typ   min   max
dV/dt_r   0.431/2.327n   0.368/2.492n   0.497/2.271n
dV/dt_f   0.426/2.412n   0.370/2.505n   0.488/2.408n
R_load = 50.000
[Rising Waveform]
R_fixture= 50.000
V_fixture= 0.0
V_fixture_min= 0.0
V_fixture_max= 0.0
|time   V(typ)   V(min)   V(max)
0s        21.16nV    961.3nV    2.149nV
2.524ns   8.51mV     11.26mV    19.57mV
2.996ns   45.11mV    41.8mV     80.53mV
3.415ns   104.8mV    87.2mV     171.4mV
4.663ns   379.4mV    298.4mV    501.7mV
5.379ns   512.8mV    414.1mV    633.3mV
6.678ns   620.9mV    521.4mV    729.5mV
9.019ns   689.9mV    588.5mV    796.6mV
13.58ns   717.8mV    612.7mV    828.3mV
50ns      718.3mV    613.2mV    828.9mV
[Rising Waveform]
R_fixture= 50.000
V_fixture= 1.200
V_fixture_min= 1.160
V_fixture_max= 1.240
|time   V(typ)   V(min)   V(max)
0s        490.1mV    543mV      426.3mV
466ps     491.1mV    543.7mV    430.4mV
536ps     490.9mV    543.9mV    558mV
609ps     502.9mV    544mV      772.7mV
752ps     786.4mV    547.9mV    1.017V
922ps     1.028V     792.5mV    1.15V
1.122ns   1.137V     1.026V     1.206V
1.332ns   1.176V     1.111V     1.226V
1.63ns    1.193V     1.147V     1.236V
50ns      1.2V       1.16V      1.24V
[Falling Waveform]
R_fixture= 50.000
V_fixture= 1.200
V_fixture_min= 1.160
V_fixture_max= 1.240
|time   V(typ)   V(min)   V(max)
0s        1.2V       1.16V      1.24V
3.461ns   1.186V     1.14V      1.217V
3.951ns   1.149V     1.105V     1.163V
4.425ns   1.085V     1.05V      1.075V
5.705ns   814.7mV    825.8mV    756.9mV
6.611ns   668.7mV    699.4mV    609.5mV
7.914ns   577.8mV    616.7mV    521.6mV
10.32ns   513.3mV    561.1mV    454.8mV
14.79ns   490.6mV    543.7mV    426.9mV
50ns      490mV      543mV      426.2mV
[Falling Waveform]
R_fixture= 50.000
V_fixture= 0.0
V_fixture_min= 0.0
V_fixture_max= 0.0
|time   V(typ)   V(min)   V(max)
0s        718.2mV    613.2mV    828.9mV
531ps     717.8mV    613.1mV    819.9mV
621ps     718.5mV    612.9mV    657mV
694ps     700.4mV    613mV      449.7mV
844ps     424.7mV    608.2mV    217mV
986ps     215.1mV    453.9mV    109.1mV
1.101ns   125mV      273.4mV    57.86mV
1.21ns    70.41mV    165.9mV    31.64mV
1.606ns   8.806mV    22.45mV    4.255mV
50ns      960.4nV    2.023uV    604.6nV
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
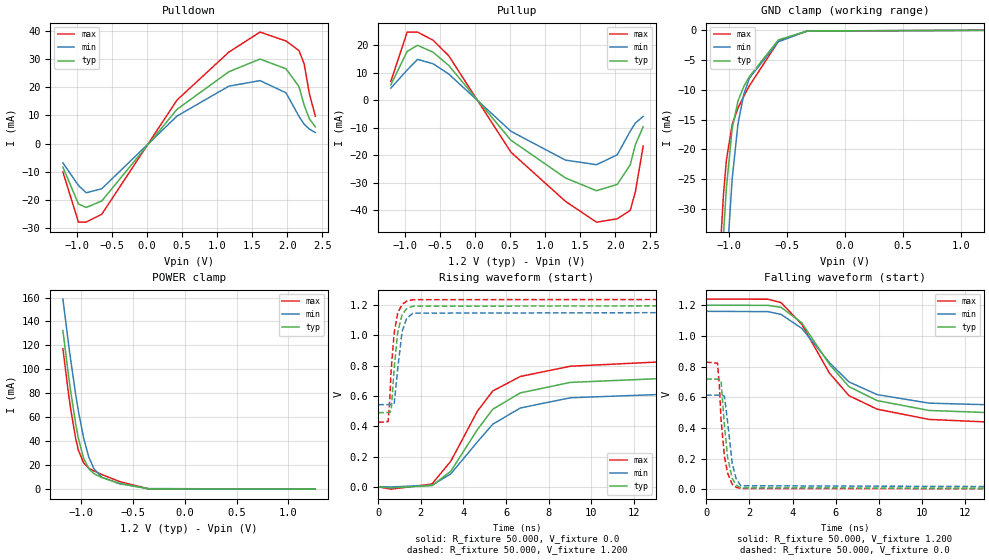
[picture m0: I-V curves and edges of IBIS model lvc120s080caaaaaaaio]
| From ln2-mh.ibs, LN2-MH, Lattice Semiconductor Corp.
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|   Model lvc120s080caaaaaaaio
[Model] lvc120s080caaaaaaaio
Model_type I/O
Polarity   Non-Inverting
Enable   Active-Low
Vinl =  0.420V
Vinh =  0.780V
Vmeas =  0.600V
Cref =  0.0F
Rref =  1.000M
Vref =  0.0V
C_comp   2.000pF   1.500pF   2.500pF
[Temperature Range]   25.000   0.125k   -40.000
[Voltage Range]   1.200V   1.160V   1.240V
[C Comp Corner]
C_comp   2.000pF   1.500pF   2.500pF
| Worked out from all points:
|   slope of the pulldown table from 0 to 0.18 V, typ, clamps not added: 31.9 ohm
|   slope of the pullup table from 0 to 0.18 V, typ, clamps not added: 31.6 ohm
|   GND clamp passes 1 mA (typ) near -0.53 V on its own axis
|   POWER clamp passes 1 mA (typ) near -0.43 V on its own axis
|   rising waveform, R_fixture 50.000, V_fixture 0.0: 20-80 % time 2.33ns typ, 2.49ns min, 2.26ns max; typ from 0 V to 0.718 V
|   rising waveform, R_fixture 50.000, V_fixture 1.200: 20-80 % time 270ps typ, 284ps min, 261ps max; typ from 0.49 V to 1.2 V
|   falling waveform, R_fixture 50.000, V_fixture 1.200: 20-80 % time 2.41ns typ, 2.48ns min, 2.41ns max; typ from 1.2 V to 0.49 V
|   falling waveform, R_fixture 50.000, V_fixture 0.0: 20-80 % time 296ps typ, 313ps min, 284ps max; typ from 0.718 V to 0 V
[Pulldown]
|Voltage   I(typ)   I(min)   I(max)
-1.2V     -8.31mA    -6.783mA   -10.01mA
-978mV    -21.32mA   -14.78mA   -27.77mA
-867mV    -22.57mA   -17.37mA   -27.71mA
-645mV    -20.24mA   -15.92mA   -24.94mA
428mV     12.17mA    9.784mA    15.46mA
1.168V    25.47mA    20.36mA    32.41mA
1.612V    29.93mA    22.31mA    39.48mA
1.982V    26.49mA    18mA       36.33mA
2.167V    20.22mA    9.693mA    32.97mA
2.241V    13.64mA    6.877mA    28.25mA
2.315V    8.821mA    5.157mA    17.77mA
2.4V      5.967mA    3.963mA    9.716mA
[Pullup]
|Voltage   I(typ)   I(min)   I(max)
-1.2V     5.598mA    4.42mA     6.864mA
-967mV    17.81mA    11.04mA    24.84mA
-819mV    20.05mA    14.91mA    24.86mA
-597mV    17.52mA    13.31mA    21.9mA
-375mV    12.72mA    9.609mA    16.26mA
513mV     -14.56mA   -11.31mA   -18.92mA
1.29V     -28.32mA   -21.81mA   -36.84mA
1.734V    -32.98mA   -23.5mA    -44.46mA
2.03V     -30.68mA   -19.88mA   -43.22mA
2.215V    -23.51mA   -11.26mA   -40.15mA
2.289V    -16.11mA   -8.282mA   -33.26mA
2.4V      -9.643mA   -5.87mA    -16.68mA
[GND_clamp]
|Voltage   I(typ)   I(min)   I(max)
-1.2V     -115.8mA   -133.1mA   -106.7mA
-1.1V     -56.15mA   -73.8mA    -46.79mA
-1.075V   -44.37mA   -61.27mA   -35.96mA
-1.05V    -34.42mA   -49.98mA   -27.62mA
-1.025V   -26.5mA    -40.1mA    -21.84mA
-975mV    -16.54mA   -25mA      -15.84mA
-925mV    -11.89mA   -15.79mA   -13.07mA
-875mV    -9.459mA   -10.78mA   -11.08mA
-825mV    -7.743mA   -8.01mA    -9.276mA
-575mV    -1.608mA   -1.904mA   -1.854mA
-325mV    -94.59uA   -107.1uA   -110.5uA
1.2V      0A         0A         0A
[POWER_clamp]
|Voltage   I(typ)   I(min)   I(max)
-1.175V   132.4mA    158.7mA    117.3mA
-1.125V   97.67mA    124.2mA    82.52mA
-1.1V     81.7mA     108mA      66.95mA
-1.05V    53.71mA    78.17mA    41.44mA
-1.025V   42.27mA    64.93mA    32.38mA
-975mV    25.71mA    42.63mA    21.87mA
-925mV    16.98mA    26.74mA    17.54mA
-875mV    12.89mA    17mA       15.15mA
-800mV    9.742mA    10mA       12.28mA
-625mV    4.793mA    4.396mA    6.256mA
-350mV    291.9uA    500.3uA    309.5uA
1.26V     0A         0A         0A
[Ramp]
| variable   typ   min   max
dV/dt_r   0.431/2.326n   0.368/2.492n   0.497/2.271n
dV/dt_f   0.426/2.413n   0.370/2.487n   0.488/2.415n
R_load = 50.000
[Rising Waveform]
R_fixture= 50.000
V_fixture= 0.0
V_fixture_min= 0.0
V_fixture_max= 0.0
|time   V(typ)   V(min)   V(max)
0s        21.16nV    961.3nV    2.149nV
616ps     -6.114mV   59.95uV    -14.63mV
2.526ns   8.616mV    11.36mV    19.74mV
3.413ns   104.5mV    86.98mV    170.9mV
4.66ns    378.9mV    298mV      501mV
5.38ns    513.1mV    414.3mV    633.5mV
6.672ns   620.6mV    521.2mV    729.2mV
9.017ns   689.9mV    588.5mV    796.6mV
13.66ns   717.8mV    612.7mV    828.4mV
50ns      718.3mV    613.2mV    828.9mV
[Rising Waveform]
R_fixture= 50.000
V_fixture= 1.200
V_fixture_min= 1.160
V_fixture_max= 1.240
|time   V(typ)   V(min)   V(max)
0s        490.1mV    543mV      426.3mV
467ps     491.1mV    543.7mV    431mV
537ps     490.9mV    543.9mV    560.4mV
609ps     502.7mV    544mV      772.8mV
749ps     779.7mV    546.9mV    1.014V
911ps     1.017V     772.7mV    1.145V
1.121ns   1.137V     1.025V     1.205V
1.332ns   1.176V     1.111V     1.226V
1.629ns   1.193V     1.147V     1.236V
50ns      1.2V       1.16V      1.24V
[Falling Waveform]
R_fixture= 50.000
V_fixture= 1.200
V_fixture_min= 1.160
V_fixture_max= 1.240
|time   V(typ)   V(min)   V(max)
0s        1.2V       1.16V      1.24V
2.866ns   1.199V     1.158V     1.239V
3.467ns   1.186V     1.14V      1.217V
4.428ns   1.085V     1.049V     1.075V
5.705ns   814.7mV    825.8mV    757.4mV
6.608ns   669mV      699.7mV    610.3mV
7.914ns   577.8mV    616.7mV    521.8mV
10.32ns   513.3mV    561.1mV    454.9mV
14.82ns   490.6mV    543.7mV    426.9mV
50ns      490mV      543mV      426.3mV
[Falling Waveform]
R_fixture= 50.000
V_fixture= 0.0
V_fixture_min= 0.0
V_fixture_max= 0.0
|time   V(typ)   V(min)   V(max)
0s        718.2mV    613.2mV    828.9mV
528ps     717.8mV    613.1mV    822mV
618ps     718.4mV    612.9mV    663.6mV
694ps     700.4mV    613mV      449.6mV
847ps     418mV      607.3mV    214mV
994ps     207.3mV    440.6mV    104.5mV
1.21ns    70.41mV    165.9mV    31.64mV
1.387ns   27.12mV    69.81mV    12.27mV
1.606ns   8.808mV    22.45mV    4.254mV
50ns      950.2nV    2.023uV    602.3nV
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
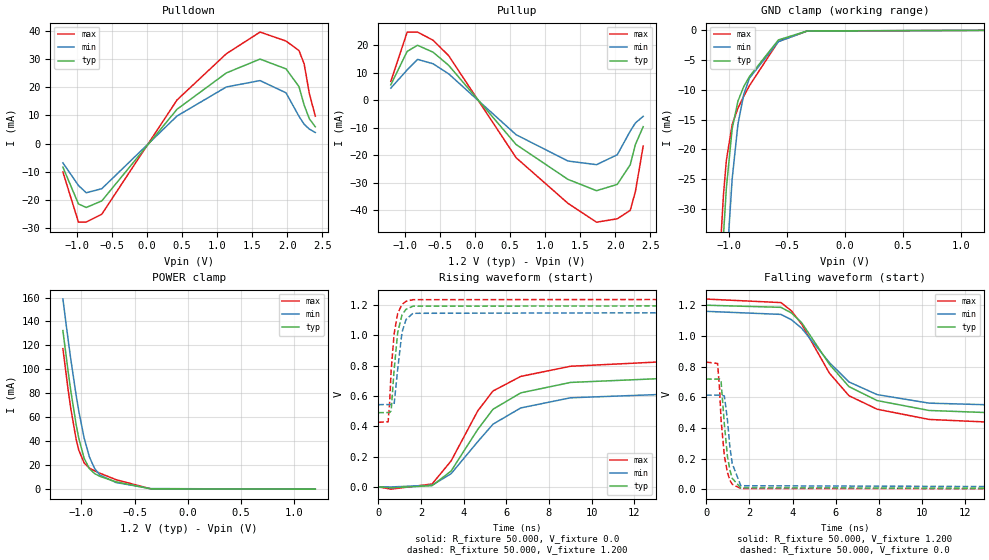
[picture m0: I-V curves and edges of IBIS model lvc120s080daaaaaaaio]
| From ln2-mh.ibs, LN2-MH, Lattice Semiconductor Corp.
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|   Model lvc120s080daaaaaaaio
[Model] lvc120s080daaaaaaaio
Model_type I/O
Polarity   Non-Inverting
Enable   Active-Low
Vinl =  0.420V
Vinh =  0.780V
Vmeas =  0.600V
Cref =  0.0F
Rref =  1.000M
Vref =  0.0V
C_comp   2.000pF   1.500pF   2.500pF
[Temperature Range]   25.000   0.125k   -40.000
[Voltage Range]   1.200V   1.160V   1.240V
[C Comp Corner]
C_comp   2.000pF   1.500pF   2.500pF
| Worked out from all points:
|   slope of the pulldown table from 0 to 0.18 V, typ, clamps not added: 31.9 ohm
|   slope of the pullup table from 0 to 0.18 V, typ, clamps not added: 31.8 ohm
|   GND clamp passes 1 mA (typ) near -0.53 V on its own axis
|   POWER clamp passes 1 mA (typ) near -0.43 V on its own axis
|   rising waveform, R_fixture 50.000, V_fixture 0.0: 20-80 % time 2.33ns typ, 2.49ns min, 2.26ns max; typ from 0 V to 0.718 V
|   rising waveform, R_fixture 50.000, V_fixture 1.200: 20-80 % time 270ps typ, 284ps min, 261ps max; typ from 0.49 V to 1.2 V
|   falling waveform, R_fixture 50.000, V_fixture 1.200: 20-80 % time 2.41ns typ, 2.48ns min, 2.4ns max; typ from 1.2 V to 0.49 V
|   falling waveform, R_fixture 50.000, V_fixture 0.0: 20-80 % time 296ps typ, 313ps min, 284ps max; typ from 0.718 V to 0 V
[Pulldown]
|Voltage   I(typ)   I(min)   I(max)
-1.2V     -8.31mA    -6.783mA   -10.01mA
-978mV    -21.32mA   -14.78mA   -27.77mA
-867mV    -22.57mA   -17.37mA   -27.71mA
-645mV    -20.24mA   -15.92mA   -24.94mA
428mV     12.17mA    9.784mA    15.46mA
1.131V    25.01mA    20.05mA    31.79mA
1.612V    29.91mA    22.31mA    39.46mA
1.982V    26.46mA    17.99mA    36.3mA
2.167V    20.2mA     9.683mA    32.94mA
2.241V    13.63mA    6.87mA     28.23mA
2.315V    8.812mA    5.151mA    17.76mA
2.4V      5.961mA    3.959mA    9.707mA
[Pullup]
|Voltage   I(typ)   I(min)   I(max)
-1.2V     5.592mA    4.415mA    6.856mA
-967mV    17.79mA    11.03mA    24.81mA
-819mV    20.03mA    14.89mA    24.83mA
-597mV    17.5mA     13.29mA    21.86mA
-375mV    12.71mA    9.614mA    16.24mA
587mV     -16.15mA   -12.58mA   -20.96mA
1.327V    -28.86mA   -22.16mA   -37.59mA
1.734V    -32.98mA   -23.5mA    -44.46mA
2.03V     -30.68mA   -19.88mA   -43.22mA
2.215V    -23.51mA   -11.26mA   -40.15mA
2.289V    -16.11mA   -8.282mA   -33.26mA
2.4V      -9.643mA   -5.87mA    -16.68mA
[GND_clamp]
|Voltage   I(typ)   I(min)   I(max)
-1.2V     -115.8mA   -133.1mA   -106.7mA
-1.1V     -56.15mA   -73.8mA    -46.79mA
-1.075V   -44.37mA   -61.27mA   -35.96mA
-1.05V    -34.42mA   -49.98mA   -27.62mA
-1.025V   -26.5mA    -40.1mA    -21.84mA
-975mV    -16.54mA   -25mA      -15.84mA
-925mV    -11.89mA   -15.79mA   -13.07mA
-875mV    -9.459mA   -10.78mA   -11.08mA
-825mV    -7.743mA   -8.01mA    -9.276mA
-575mV    -1.608mA   -1.904mA   -1.854mA
-325mV    -94.59uA   -107.1uA   -110.5uA
1.2V      -90.03nA   2.134uA    -12.11uA
[POWER_clamp]
|Voltage   I(typ)   I(min)   I(max)
-1.175V   132.4mA    158.7mA    117.3mA
-1.125V   97.68mA    124.2mA    82.53mA
-1.1V     81.71mA    108mA      66.96mA
-1.05V    53.72mA    78.17mA    41.46mA
-1.025V   42.29mA    64.94mA    32.4mA
-975mV    25.73mA    42.64mA    21.9mA
-925mV    17mA       26.75mA    17.58mA
-875mV    12.91mA    17.01mA    15.19mA
-825mV    10.65mA    11.68mA    13.24mA
-675mV    6.1mA      5.538mA    7.913mA
-350mV    294.7uA    490.5uA    329uA
1.2V      0A         0A         12.42uA
[Ramp]
| variable   typ   min   max
dV/dt_r   0.431/2.338n   0.368/2.494n   0.497/2.271n
dV/dt_f   0.426/2.412n   0.370/2.505n   0.488/2.419n
R_load = 50.000
[Rising Waveform]
R_fixture= 50.000
V_fixture= 0.0
V_fixture_min= 0.0
V_fixture_max= 0.0
|time   V(typ)   V(min)   V(max)
0s        21.16nV    961.3nV    2.149nV
615ps     -5.975mV   59.25uV    -14.65mV
2.525ns   8.555mV    11.31mV    19.66mV
3.415ns   104.8mV    87.24mV    171.4mV
4.662ns   379.2mV    298.4mV    501.4mV
5.379ns   512.8mV    414.2mV    633.3mV
6.679ns   620.9mV    521.5mV    729.6mV
9.013ns   689.8mV    588.4mV    796.5mV
13.66ns   717.8mV    612.7mV    828.4mV
50ns      718.3mV    613.2mV    828.9mV
[Rising Waveform]
R_fixture= 50.000
V_fixture= 1.200
V_fixture_min= 1.160
V_fixture_max= 1.240
|time   V(typ)   V(min)   V(max)
0s        490.1mV    543mV      426.3mV
466ps     491.1mV    543.7mV    430.3mV
535ps     491mV      543.9mV    555.8mV
608ps     501.8mV    544mV      770.2mV
746ps     773.3mV    545.9mV    1.01V
914ps     1.02V      778.1mV    1.146V
1.115ns   1.135V     1.021V     1.204V
1.304ns   1.173V     1.105V     1.225V
1.626ns   1.193V     1.146V     1.236V
50ns      1.2V       1.16V      1.24V
[Falling Waveform]
R_fixture= 50.000
V_fixture= 1.200
V_fixture_min= 1.160
V_fixture_max= 1.240
|time   V(typ)   V(min)   V(max)
0s        1.2V       1.16V      1.24V
3.462ns   1.186V     1.14V      1.217V
3.951ns   1.149V     1.105V     1.163V
4.426ns   1.085V     1.049V     1.075V
5.705ns   814.8mV    825.8mV    756.9mV
6.611ns   668.8mV    699.4mV    609.5mV
7.915ns   577.9mV    616.7mV    521.5mV
10.32ns   513.3mV    561.1mV    454.8mV
14.74ns   490.6mV    543.7mV    426.9mV
50ns      490mV      543mV      426.3mV
[Falling Waveform]
R_fixture= 50.000
V_fixture= 0.0
V_fixture_min= 0.0
V_fixture_max= 0.0
|time   V(typ)   V(min)   V(max)
0s        718.2mV    613.2mV    828.9mV
531ps     717.8mV    613.1mV    819.9mV
621ps     718.5mV    612.9mV    656.9mV
694ps     700.4mV    613mV      449.6mV
844ps     424.7mV    608.2mV    217mV
986ps     215.1mV    453.9mV    109.1mV
1.101ns   125mV      273.4mV    57.85mV
1.21ns    70.41mV    165.9mV    31.65mV
1.606ns   8.806mV    22.45mV    4.255mV
50ns      958.7nV    2.023uV    603.7nV
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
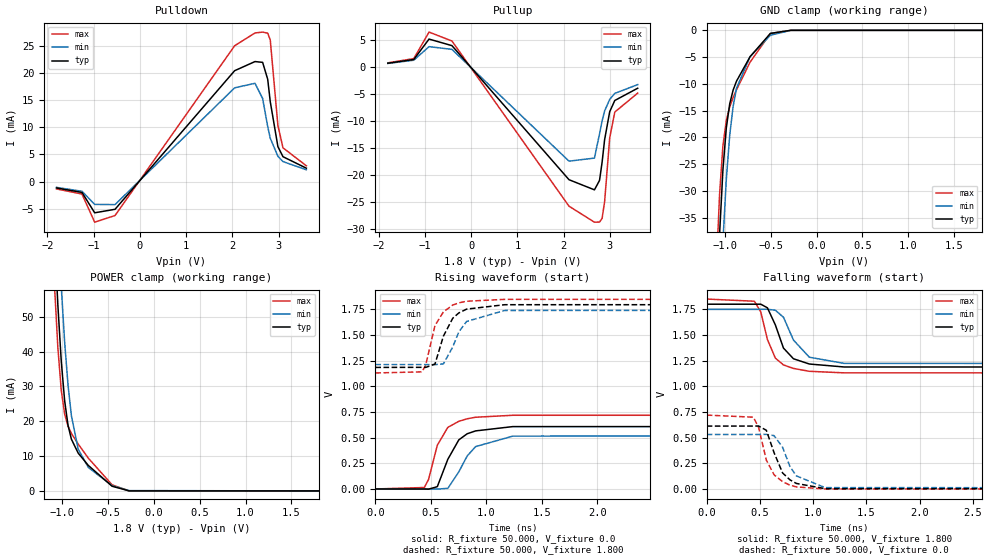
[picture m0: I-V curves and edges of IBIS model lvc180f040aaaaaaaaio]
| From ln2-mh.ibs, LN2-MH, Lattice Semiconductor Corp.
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|   Model lvc180f040aaaaaaaaio
[Model] lvc180f040aaaaaaaaio
Model_type I/O
Polarity   Non-Inverting
Enable   Active-Low
Vinl =  0.630V
Vinh =  1.170V
Vmeas =  0.900V
Cref =  0.0F
Rref =  1.000M
Vref =  0.0V
C_comp   2.000pF   1.500pF   2.500pF
[Temperature Range]   25.000   0.125k   -40.000
[Voltage Range]   1.800V   1.750V   1.850V
[C Comp Corner]
C_comp   2.000pF   1.500pF   2.500pF
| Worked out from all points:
|   slope of the pulldown table from 0 to 0.27 V, typ, clamps not added: 98.3 ohm
|   slope of the pullup table from 0 to 0.27 V, typ, clamps not added: 98.7 ohm
|   GND clamp passes 1 mA (typ) near -0.54 V on its own axis
|   POWER clamp passes 1 mA (typ) near -0.43 V on its own axis
|   rising waveform, R_fixture 50.000, V_fixture 0.0: 20-80 % time 162ps typ, 194ps min, 140ps max; typ from 0 V to 0.614 V
|   rising waveform, R_fixture 50.000, V_fixture 1.800: 20-80 % time 141ps typ, 157ps min, 129ps max; typ from 1.18 V to 1.8 V
|   falling waveform, R_fixture 50.000, V_fixture 1.800: 20-80 % time 148ps typ, 172ps min, 132ps max; typ from 1.8 V to 1.18 V
|   falling waveform, R_fixture 50.000, V_fixture 0.0: 20-80 % time 147ps typ, 162ps min, 135ps max; typ from 0.614 V to 0 V
[Pulldown]
|Voltage   I(typ)   I(min)   I(max)
-1.8V     -1.177mA   -1.065mA   -1.357mA
-1.25V    -1.996mA   -1.784mA   -2.29mA
-975mV    -5.74mA    -4.198mA   -7.469mA
-535mV    -5.098mA   -4.235mA   -6.24mA
2.05V     20.39mA    17.24mA    24.98mA
2.49V     22.07mA    18.07mA    27.33mA
2.655V    21.92mA    15.28mA    27.49mA
2.765V    18.79mA    10.1mA     27.29mA
2.82V     14.69mA    7.967mA    26.04mA
2.985V    6.431mA    4.647mA    10.31mA
3.095V    4.574mA    3.677mA    6.203mA
3.6V      2.462mA    2.162mA    2.901mA
[Pullup]
|Voltage   I(typ)   I(min)   I(max)
-1.8V     652.6uA    617.7uA    718uA
-1.24V    1.342mA    1.21mA     1.513mA
-910mV    5.133mA    3.729mA    6.429mA
-415mV    3.914mA    3.222mA    4.773mA
2.115V    -20.95mA   -17.51mA   -25.86mA
2.665V    -22.83mA   -16.94mA   -28.83mA
2.775V    -21.08mA   -12.45mA   -28.8mA
2.83V     -17.74mA   -10.06mA   -28.14mA
2.885V    -13.52mA   -8.199mA   -25.02mA
2.995V    -8.328mA   -6.044mA   -13.18mA
3.105V    -6.254mA   -4.938mA   -8.404mA
3.6V      -3.983mA   -3.31mA    -4.885mA
[GND_clamp]
|Voltage   I(typ)   I(min)   I(max)
-1.8V     -585.7mA   -591.6mA   -585.2mA
-1.097V   -54.7mA    -72.3mA    -45.44mA
-1.06V    -38.22mA   -54.4mA    -30.73mA
-1.023V   -26.04mA   -39.44mA   -21.56mA
-986mV    -18.22mA   -27.85mA   -16.81mA
-949mV    -13.75mA   -19.63mA   -14.29mA
-912mV    -11.19mA   -14.24mA   -12.58mA
-875mV    -9.506mA   -10.84mA   -11.12mA
-727mV    -4.941mA   -4.928mA   -5.958mA
-505mV    -576.1uA   -916.7uA   -589.6uA
-283mV    -824.2nA   -10.84uA   -168.9nA
1.8V      0A         0A         0A
[POWER_clamp]
|Voltage   I(typ)   I(min)   I(max)
-1.789V   650.9mA    666.7mA    643.9mA
-1.086V   73.37mA    99.35mA    59.09mA
-1.049V   53.37mA    77.75mA    41.19mA
-1.012V   37.31mA    58.71mA    28.94mA
-975mV    25.9mA     42.77mA    22.1mA
-938mV    18.85mA    30.42mA    18.6mA
-901mV    14.84mA    21.56mA    16.51mA
-827mV    10.86mA    11.99mA    13.46mA
-716mV    7.305mA    6.728mA    9.397mA
-457mV    1.344mA    1.526mA    1.755mA
-272mV    20.87uA    98.79uA    12.36uA
1.8V      0A         0A         0A
[Ramp]
| variable   typ   min   max
dV/dt_r   0.368/0.163n   0.319/0.196n   0.432/0.140n
dV/dt_f   0.369/0.149n   0.323/0.172n   0.432/0.133n
R_load = 50.000
[Rising Waveform]
R_fixture= 50.000
V_fixture= 0.0
V_fixture_min= 0.0
V_fixture_max= 0.0
|time   V(typ)   V(min)   V(max)
0s        816.5nV    7.287uV    250.2nV
441ps     -167.9uV   -60.93uV   14.26mV
479ps     -1.907mV   23.67uV    92.5mV
558ps     22.43mV    -1.144mV   426mV
653ps     289.6mV    6.149mV    600.4mV
752ps     478.7mV    167mV      659.2mV
827ps     537.8mV    321.2mV    683.8mV
903ps     565.7mV    412.6mV    698.7mV
1.238ns   607.6mV    515mV      718mV
50ns      613.9mV    532.4mV    720.7mV
[Rising Waveform]
R_fixture= 50.000
V_fixture= 1.800
V_fixture_min= 1.750
V_fixture_max= 1.850
|time   V(typ)   V(min)   V(max)
0s        1.184V     1.212V     1.13V
420ps     1.185V     1.212V     1.141V
453ps     1.184V     1.212V     1.205V
537ps     1.217V     1.211V     1.592V
613ps     1.489V     1.219V     1.725V
697ps     1.663V     1.383V     1.792V
752ps     1.715V     1.531V     1.813V
822ps     1.752V     1.632V     1.829V
1.165ns   1.795V     1.739V     1.847V
50ns      1.8V       1.75V      1.85V
[Falling Waveform]
R_fixture= 50.000
V_fixture= 1.800
V_fixture_min= 1.750
V_fixture_max= 1.850
|time   V(typ)   V(min)   V(max)
0s        1.8V       1.75V      1.85V
448ps     1.8V       1.75V      1.829V
508ps     1.8V       1.75V      1.725V
570ps     1.765V     1.751V     1.457V
645ps     1.598V     1.741V     1.275V
721ps     1.373V     1.673V     1.209V
815ps     1.269V     1.451V     1.175V
964ps     1.218V     1.284V     1.147V
1.291ns   1.189V     1.224V     1.132V
50ns      1.184V     1.212V     1.13V
[Falling Waveform]
R_fixture= 50.000
V_fixture= 0.0
V_fixture_min= 0.0
V_fixture_max= 0.0
|time   V(typ)   V(min)   V(max)
0s        613.9mV    532.4mV    720.7mV
438ps     614.1mV    532.3mV    700.4mV
487ps     614.7mV    532.4mV    603.3mV
560ps     572.9mV    533.3mV    282.6mV
633ps     354.3mV    520.7mV    139.6mV
713ps     157.7mV    407.4mV    72.82mV
782ps     90.87mV    220mV      39.1mV
842ps     55.65mV    129.4mV    22.18mV
1.112ns   5.246mV    15.09mV    1.803mV
50ns      2.784uV    8.325uV    1.683uV
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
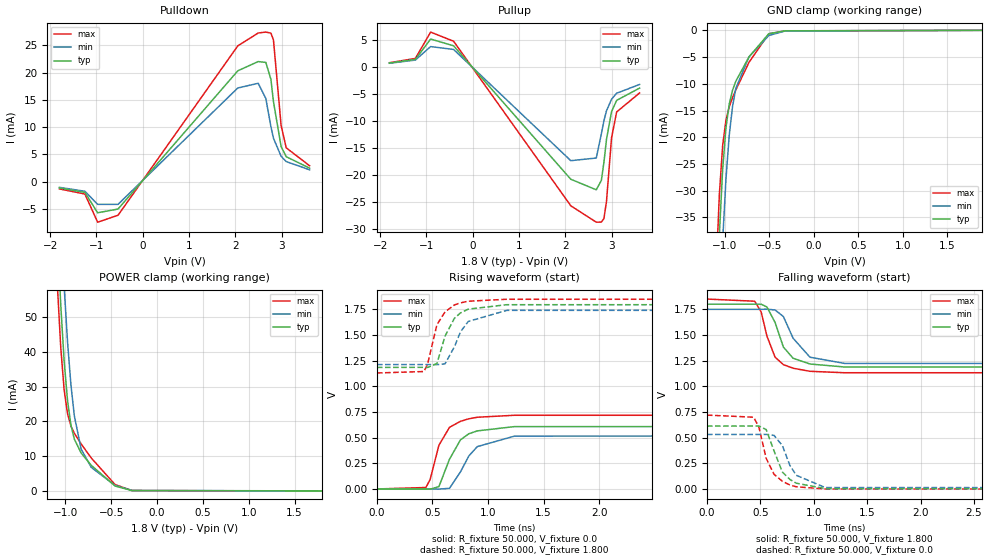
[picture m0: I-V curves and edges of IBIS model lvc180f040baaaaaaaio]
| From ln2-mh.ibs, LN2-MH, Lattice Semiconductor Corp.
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|   Model lvc180f040baaaaaaaio
[Model] lvc180f040baaaaaaaio
Model_type I/O
Polarity   Non-Inverting
Enable   Active-Low
Vinl =  0.630V
Vinh =  1.170V
Vmeas =  0.900V
Cref =  0.0F
Rref =  1.000M
Vref =  0.0V
C_comp   2.000pF   1.500pF   2.500pF
[Temperature Range]   25.000   0.125k   -40.000
[Voltage Range]   1.800V   1.750V   1.850V
[C Comp Corner]
C_comp   2.000pF   1.500pF   2.500pF
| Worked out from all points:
|   slope of the pulldown table from 0 to 0.27 V, typ, clamps not added: 98.3 ohm
|   slope of the pullup table from 0 to 0.27 V, typ, clamps not added: 101 ohm
|   GND clamp passes 1 mA (typ) near -0.54 V on its own axis
|   POWER clamp passes 1 mA (typ) near -0.43 V on its own axis
|   rising waveform, R_fixture 50.000, V_fixture 0.0: 20-80 % time 162ps typ, 194ps min, 140ps max; typ from 0 V to 0.614 V
|   rising waveform, R_fixture 50.000, V_fixture 1.800: 20-80 % time 141ps typ, 156ps min, 129ps max; typ from 1.18 V to 1.8 V
|   falling waveform, R_fixture 50.000, V_fixture 1.800: 20-80 % time 148ps typ, 171ps min, 132ps max; typ from 1.8 V to 1.18 V
|   falling waveform, R_fixture 50.000, V_fixture 0.0: 20-80 % time 147ps typ, 161ps min, 135ps max; typ from 0.614 V to 0 V
[Pulldown]
|Voltage   I(typ)   I(min)   I(max)
-1.8V     -1.176mA   -1.063mA   -1.356mA
-1.25V    -1.992mA   -1.78mA    -2.288mA
-975mV    -5.728mA   -4.186mA   -7.458mA
-535mV    -5.045mA   -4.187mA   -6.188mA
2.05V     20.33mA    17.18mA    24.91mA
2.49V     22.03mA    18.04mA    27.27mA
2.655V    21.88mA    15.26mA    27.44mA
2.765V    18.76mA    10.08mA    27.25mA
2.82V     14.67mA    7.953mA    26mA
2.985V    6.421mA    4.64mA     10.3mA
3.095V    4.566mA    3.671mA    6.195mA
3.6V      2.459mA    2.158mA    2.897mA
[Pullup]
|Voltage   I(typ)   I(min)   I(max)
-1.8V     648.7uA    614uA      713.9uA
-1.24V    1.334mA    1.203mA    1.504mA
-910mV    5.097mA    3.702mA    6.385mA
-415mV    3.846mA    3.17mA     4.694mA
2.115V    -20.86mA   -17.42mA   -25.77mA
2.665V    -22.81mA   -16.93mA   -28.81mA
2.775V    -21.07mA   -12.44mA   -28.79mA
2.83V     -17.73mA   -10.05mA   -28.13mA
2.885V    -13.51mA   -8.193mA   -25.01mA
2.995V    -8.324mA   -6.04mA    -13.17mA
3.105V    -6.251mA   -4.935mA   -8.401mA
3.6V      -3.982mA   -3.308mA   -4.883mA
[GND_clamp]
|Voltage   I(typ)   I(min)   I(max)
-1.8V     -585.7mA   -591.6mA   -585.2mA
-1.097V   -54.7mA    -72.3mA    -45.45mA
-1.06V    -38.22mA   -54.4mA    -30.73mA
-1.023V   -26.05mA   -39.45mA   -21.57mA
-986mV    -18.23mA   -27.86mA   -16.82mA
-949mV    -13.77mA   -19.64mA   -14.3mA
-912mV    -11.21mA   -14.25mA   -12.59mA
-875mV    -9.522mA   -10.86mA   -11.14mA
-727mV    -4.965mA   -4.953mA   -5.98mA
-505mV    -637.4uA   -970.8uA   -651.9uA
-320mV    -95.22uA   -117.2uA   -94.14uA
1.89V     0A         0A         0A
[POWER_clamp]
|Voltage   I(typ)   I(min)   I(max)
-1.789V   650.9mA    666.7mA    643.9mA
-1.086V   73.39mA    99.36mA    59.11mA
-1.049V   53.39mA    77.76mA    41.22mA
-1.012V   37.33mA    58.73mA    28.98mA
-975mV    25.93mA    42.79mA    22.14mA
-938mV    18.88mA    30.44mA    18.64mA
-901mV    14.88mA    21.59mA    16.55mA
-827mV    10.9mA     12.03mA    13.51mA
-716mV    7.349mA    6.765mA    9.446mA
-457mV    1.407mA    1.575mA    1.826mA
-272mV    92.84uA    154.8uA    100.2uA
1.8V      0A         0A         0A
[Ramp]
| variable   typ   min   max
dV/dt_r   0.368/0.163n   0.319/0.196n   0.432/0.140n
dV/dt_f   0.369/0.148n   0.323/0.172n   0.432/0.133n
R_load = 50.000
[Rising Waveform]
R_fixture= 50.000
V_fixture= 0.0
V_fixture_min= 0.0
V_fixture_max= 0.0
|time   V(typ)   V(min)   V(max)
0s        816.5nV    7.287uV    250.2nV
441ps     -167.8uV   -60.97uV   14.26mV
479ps     -1.907mV   23.64uV    92.5mV
558ps     22.43mV    -1.143mV   426mV
653ps     289.6mV    6.149mV    600.4mV
752ps     478.7mV    167mV      659.2mV
827ps     537.8mV    321.2mV    683.8mV
903ps     565.7mV    412.6mV    698.7mV
1.238ns   607.6mV    515mV      718mV
50ns      613.9mV    532.4mV    720.7mV
[Rising Waveform]
R_fixture= 50.000
V_fixture= 1.800
V_fixture_min= 1.750
V_fixture_max= 1.850
|time   V(typ)   V(min)   V(max)
0s        1.184V     1.212V     1.13V
423ps     1.185V     1.212V     1.144V
456ps     1.184V     1.212V     1.216V
540ps     1.221V     1.211V     1.6V
613ps     1.489V     1.219V     1.725V
698ps     1.664V     1.386V     1.793V
752ps     1.715V     1.531V     1.813V
822ps     1.752V     1.632V     1.829V
1.168ns   1.795V     1.74V      1.848V
50ns      1.8V       1.75V      1.85V
[Falling Waveform]
R_fixture= 50.000
V_fixture= 1.800
V_fixture_min= 1.750
V_fixture_max= 1.850
|time   V(typ)   V(min)   V(max)
0s        1.8V       1.75V      1.85V
448ps     1.8V       1.75V      1.829V
508ps     1.8V       1.75V      1.725V
562ps     1.773V     1.751V     1.49V
638ps     1.623V     1.744V     1.285V
716ps     1.383V     1.68V      1.212V
807ps     1.274V     1.469V     1.177V
965ps     1.218V     1.284V     1.147V
1.288ns   1.189V     1.224V     1.133V
50ns      1.184V     1.212V     1.13V
[Falling Waveform]
R_fixture= 50.000
V_fixture= 0.0
V_fixture_min= 0.0
V_fixture_max= 0.0
|time   V(typ)   V(min)   V(max)
0s        613.9mV    532.4mV    720.7mV
438ps     614.1mV    532.3mV    700.4mV
487ps     614.8mV    532.4mV    603.3mV
555ps     580mV      533.2mV    299.8mV
629ps     370.6mV    522.8mV    144.2mV
707ps     166.3mV    422.8mV    76.59mV
777ps     94.65mV    231.2mV    40.97mV
837ps     58.15mV    134.9mV    23.25mV
1.108ns   5.439mV    15.61mV    1.868mV
50ns      2.782uV    8.325uV    1.683uV
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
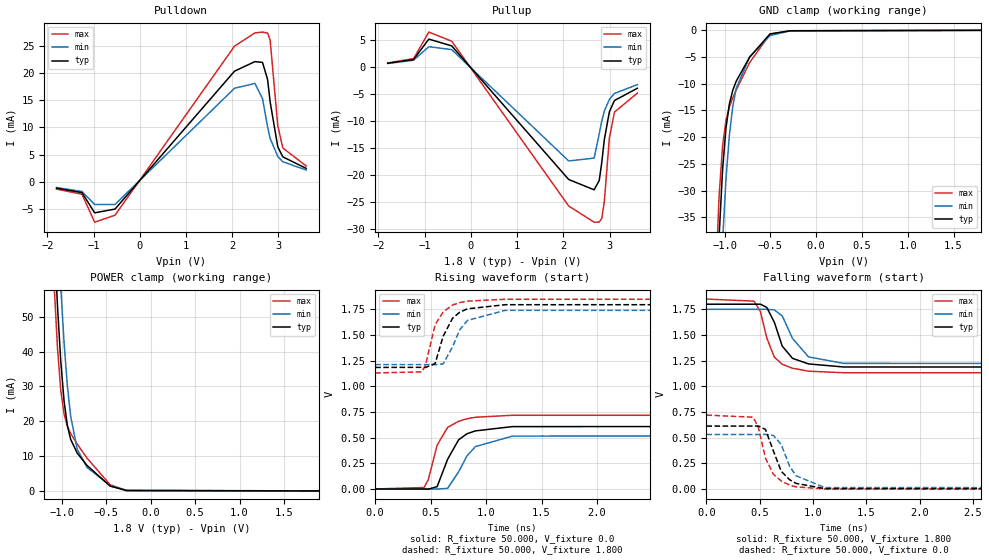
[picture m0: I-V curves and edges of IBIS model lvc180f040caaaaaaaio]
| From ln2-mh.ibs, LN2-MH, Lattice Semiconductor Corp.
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|   Model lvc180f040caaaaaaaio
[Model] lvc180f040caaaaaaaio
Model_type I/O
Polarity   Non-Inverting
Enable   Active-Low
Vinl =  0.630V
Vinh =  1.170V
Vmeas =  0.900V
Cref =  0.0F
Rref =  1.000M
Vref =  0.0V
C_comp   2.000pF   1.500pF   2.500pF
[Temperature Range]   25.000   0.125k   -40.000
[Voltage Range]   1.800V   1.750V   1.850V
[C Comp Corner]
C_comp   2.000pF   1.500pF   2.500pF
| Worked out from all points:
|   slope of the pulldown table from 0 to 0.27 V, typ, clamps not added: 101 ohm
|   slope of the pullup table from 0 to 0.27 V, typ, clamps not added: 98.7 ohm
|   GND clamp passes 1 mA (typ) near -0.53 V on its own axis
|   POWER clamp passes 1 mA (typ) near -0.43 V on its own axis
|   rising waveform, R_fixture 50.000, V_fixture 0.0: 20-80 % time 162ps typ, 194ps min, 140ps max; typ from 0 V to 0.614 V
|   rising waveform, R_fixture 50.000, V_fixture 1.800: 20-80 % time 141ps typ, 156ps min, 129ps max; typ from 1.18 V to 1.8 V
|   falling waveform, R_fixture 50.000, V_fixture 1.800: 20-80 % time 148ps typ, 171ps min, 132ps max; typ from 1.8 V to 1.18 V
|   falling waveform, R_fixture 50.000, V_fixture 0.0: 20-80 % time 147ps typ, 162ps min, 135ps max; typ from 0.614 V to 0 V
[Pulldown]
|Voltage   I(typ)   I(min)   I(max)
-1.8V     -1.169mA   -1.058mA   -1.348mA
-1.25V    -1.982mA   -1.771mA   -2.275mA
-975mV    -5.695mA   -4.164mA   -7.413mA
-535mV    -5.006mA   -4.165mA   -6.129mA
2.05V     20.3mA     17.16mA    24.89mA
2.49V     22.05mA    18.05mA    27.31mA
2.655V    21.91mA    15.27mA    27.47mA
2.765V    18.78mA    10.09mA    27.28mA
2.82V     14.68mA    7.961mA    26.03mA
2.985V    6.428mA    4.644mA    10.31mA
3.095V    4.572mA    3.675mA    6.202mA
3.6V      2.462mA    2.161mA    2.9mA
[Pullup]
|Voltage   I(typ)   I(min)   I(max)
-1.8V     651.5uA    616.3uA    717.1uA
-1.24V    1.339mA    1.207mA    1.511mA
-910mV    5.121mA    3.716mA    6.418mA
-415mV    3.859mA    3.169mA    4.721mA
2.115V    -20.86mA   -17.43mA   -25.77mA
2.665V    -22.77mA   -16.9mA    -28.76mA
2.775V    -21.04mA   -12.42mA   -28.74mA
2.83V     -17.71mA   -10.04mA   -28.08mA
2.885V    -13.49mA   -8.181mA   -24.97mA
2.995V    -8.311mA   -6.031mA   -13.15mA
3.105V    -6.242mA   -4.928mA   -8.389mA
3.6V      -3.975mA   -3.303mA   -4.876mA
[GND_clamp]
|Voltage   I(typ)   I(min)   I(max)
-1.8V     -585.7mA   -591.6mA   -585.2mA
-1.097V   -54.72mA   -72.32mA   -45.47mA
-1.06V    -38.25mA   -54.42mA   -30.77mA
-1.023V   -26.08mA   -39.47mA   -21.61mA
-986mV    -18.26mA   -27.88mA   -16.87mA
-949mV    -13.8mA    -19.67mA   -14.35mA
-912mV    -11.24mA   -14.28mA   -12.64mA
-875mV    -9.559mA   -10.89mA   -11.19mA
-727mV    -5.003mA   -4.98mA    -6.032mA
-505mV    -676uA     -991.2uA   -711.7uA
-283mV    -81.53uA   -80.08uA   -96.55uA
1.8V      0A         0A         0A
[POWER_clamp]
|Voltage   I(typ)   I(min)   I(max)
-1.789V   650.9mA    666.7mA    643.9mA
-1.086V   73.38mA    99.35mA    59.1mA
-1.049V   53.37mA    77.75mA    41.2mA
-1.012V   37.32mA    58.72mA    28.95mA
-975mV    25.91mA    42.78mA    22.11mA
-938mV    18.86mA    30.43mA    18.61mA
-901mV    14.86mA    21.58mA    16.52mA
-827mV    10.88mA    12.01mA    13.47mA
-716mV    7.324mA    6.749mA    9.413mA
-457mV    1.39mA     1.571mA    1.797mA
-272mV    110.1uA    181.7uA    102.9uA
1.89V     0A         0A         0A
[Ramp]
| variable   typ   min   max
dV/dt_r   0.368/0.163n   0.319/0.196n   0.432/0.140n
dV/dt_f   0.369/0.148n   0.323/0.172n   0.432/0.133n
R_load = 50.000
[Rising Waveform]
R_fixture= 50.000
V_fixture= 0.0
V_fixture_min= 0.0
V_fixture_max= 0.0
|time   V(typ)   V(min)   V(max)
0s        816.5nV    7.287uV    250.2nV
441ps     -171.1uV   -60.79uV   14.26mV
479ps     -1.911mV   23.81uV    92.5mV
558ps     22.58mV    -1.147mV   426mV
653ps     289.8mV    6.184mV    600.4mV
752ps     478.8mV    167.2mV    659.2mV
827ps     537.9mV    321.4mV    683.8mV
903ps     565.7mV    412.7mV    698.7mV
1.238ns   607.6mV    515mV      718mV
50ns      613.9mV    532.4mV    720.7mV
[Rising Waveform]
R_fixture= 50.000
V_fixture= 1.800
V_fixture_min= 1.750
V_fixture_max= 1.850
|time   V(typ)   V(min)   V(max)
0s        1.184V     1.212V     1.13V
420ps     1.185V     1.212V     1.141V
453ps     1.184V     1.212V     1.205V
540ps     1.221V     1.211V     1.6V
613ps     1.489V     1.219V     1.725V
698ps     1.664V     1.386V     1.792V
762ps     1.722V     1.551V     1.816V
832ps     1.755V     1.642V     1.83V
1.172ns   1.795V     1.74V      1.848V
50ns      1.8V       1.75V      1.85V
[Falling Waveform]
R_fixture= 50.000
V_fixture= 1.800
V_fixture_min= 1.750
V_fixture_max= 1.850
|time   V(typ)   V(min)   V(max)
0s        1.8V       1.75V      1.85V
447ps     1.8V       1.75V      1.83V
507ps     1.8V       1.75V      1.728V
566ps     1.769V     1.751V     1.473V
638ps     1.623V     1.744V     1.285V
711ps     1.393V     1.687V     1.215V
808ps     1.273V     1.467V     1.177V
958ps     1.219V     1.287V     1.148V
1.288ns   1.189V     1.224V     1.133V
50ns      1.184V     1.212V     1.13V
[Falling Waveform]
R_fixture= 50.000
V_fixture= 0.0
V_fixture_min= 0.0
V_fixture_max= 0.0
|time   V(typ)   V(min)   V(max)
0s        613.9mV    532.4mV    720.7mV
438ps     614.1mV    532.3mV    700.4mV
487ps     614.7mV    532.4mV    603.3mV
554ps     581.2mV    533.2mV    303.3mV
629ps     370.8mV    522.7mV    144.2mV
702ps     173.9mV    434.7mV    79.85mV
781ps     91.74mV    222.5mV    39.46mV
841ps     56.22mV    130.6mV    22.38mV
1.111ns   5.3mV      15.23mV    1.818mV
50ns      2.784uV    8.327uV    1.683uV
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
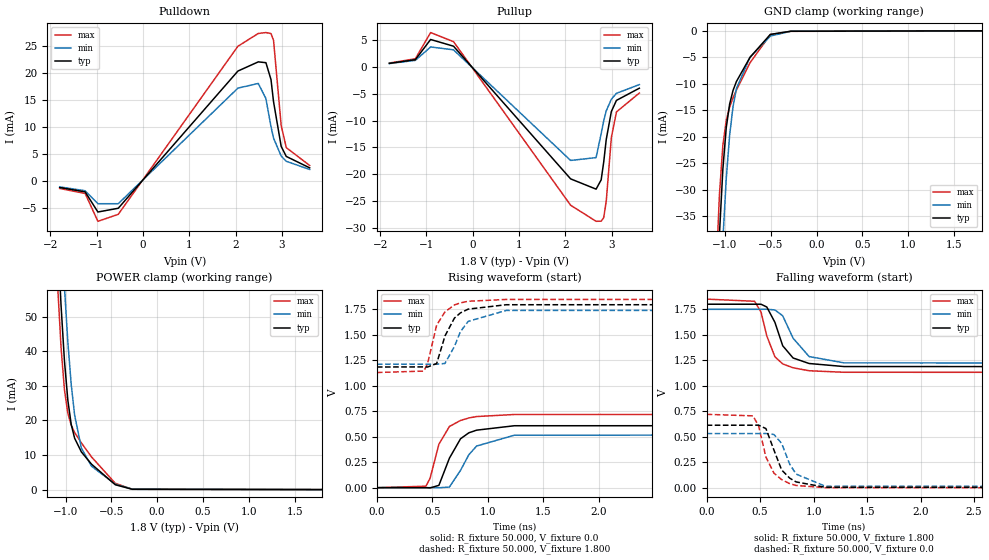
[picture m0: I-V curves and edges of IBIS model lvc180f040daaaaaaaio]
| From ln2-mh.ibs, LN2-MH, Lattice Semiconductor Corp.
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|   Model lvc180f040daaaaaaaio
[Model] lvc180f040daaaaaaaio
Model_type I/O
Polarity   Non-Inverting
Enable   Active-Low
Vinl =  0.630V
Vinh =  1.170V
Vmeas =  0.900V
Cref =  0.0F
Rref =  1.000M
Vref =  0.0V
C_comp   2.000pF   1.500pF   2.500pF
[Temperature Range]   25.000   0.125k   -40.000
[Voltage Range]   1.800V   1.750V   1.850V
[C Comp Corner]
C_comp   2.000pF   1.500pF   2.500pF
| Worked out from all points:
|   slope of the pulldown table from 0 to 0.27 V, typ, clamps not added: 101 ohm
|   slope of the pullup table from 0 to 0.27 V, typ, clamps not added: 101 ohm
|   GND clamp passes 1 mA (typ) near -0.53 V on its own axis
|   POWER clamp passes 1 mA (typ) near -0.43 V on its own axis
|   rising waveform, R_fixture 50.000, V_fixture 0.0: 20-80 % time 162ps typ, 194ps min, 140ps max; typ from 0 V to 0.614 V
|   rising waveform, R_fixture 50.000, V_fixture 1.800: 20-80 % time 141ps typ, 157ps min, 129ps max; typ from 1.18 V to 1.8 V
|   falling waveform, R_fixture 50.000, V_fixture 1.800: 20-80 % time 148ps typ, 172ps min, 132ps max; typ from 1.8 V to 1.18 V
|   falling waveform, R_fixture 50.000, V_fixture 0.0: 20-80 % time 147ps typ, 161ps min, 135ps max; typ from 0.614 V to 0 V
[Pulldown]
|Voltage   I(typ)   I(min)   I(max)
-1.8V     -1.169mA   -1.058mA   -1.348mA
-1.25V    -1.982mA   -1.771mA   -2.275mA
-975mV    -5.695mA   -4.164mA   -7.413mA
-535mV    -5.006mA   -4.165mA   -6.129mA
2.05V     20.33mA    17.18mA    24.91mA
2.49V     22.03mA    18.04mA    27.27mA
2.655V    21.88mA    15.26mA    27.44mA
2.765V    18.76mA    10.08mA    27.25mA
2.82V     14.67mA    7.953mA    26mA
2.985V    6.421mA    4.64mA     10.3mA
3.095V    4.566mA    3.671mA    6.195mA
3.6V      2.459mA    2.158mA    2.897mA
[Pullup]
|Voltage   I(typ)   I(min)   I(max)
-1.8V     648.7uA    614uA      713.9uA
-1.24V    1.334mA    1.203mA    1.504mA
-910mV    5.097mA    3.702mA    6.385mA
-415mV    3.846mA    3.17mA     4.694mA
2.115V    -20.86mA   -17.43mA   -25.77mA
2.665V    -22.77mA   -16.9mA    -28.76mA
2.775V    -21.04mA   -12.42mA   -28.74mA
2.83V     -17.71mA   -10.04mA   -28.08mA
2.885V    -13.49mA   -8.181mA   -24.97mA
2.995V    -8.311mA   -6.031mA   -13.15mA
3.105V    -6.242mA   -4.928mA   -8.389mA
3.6V      -3.975mA   -3.303mA   -4.876mA
[GND_clamp]
|Voltage   I(typ)   I(min)   I(max)
-1.8V     -585.7mA   -591.6mA   -585.2mA
-1.097V   -54.72mA   -72.32mA   -45.47mA
-1.06V    -38.25mA   -54.42mA   -30.77mA
-1.023V   -26.08mA   -39.47mA   -21.61mA
-986mV    -18.26mA   -27.88mA   -16.87mA
-949mV    -13.8mA    -19.67mA   -14.35mA
-912mV    -11.24mA   -14.28mA   -12.64mA
-875mV    -9.559mA   -10.89mA   -11.19mA
-727mV    -5.003mA   -4.98mA    -6.032mA
-505mV    -676uA     -991.2uA   -711.7uA
-283mV    -81.53uA   -80.08uA   -96.55uA
1.8V      -11.32nA   0A         -15.28uA
[POWER_clamp]
|Voltage   I(typ)   I(min)   I(max)
-1.789V   650.9mA    666.7mA    643.9mA
-1.086V   73.39mA    99.36mA    59.11mA
-1.049V   53.39mA    77.76mA    41.22mA
-1.012V   37.33mA    58.73mA    28.98mA
-975mV    25.93mA    42.79mA    22.14mA
-938mV    18.88mA    30.44mA    18.64mA
-901mV    14.88mA    21.59mA    16.55mA
-827mV    10.9mA     12.03mA    13.51mA
-716mV    7.349mA    6.765mA    9.446mA
-457mV    1.407mA    1.575mA    1.826mA
-272mV    92.84uA    154.8uA    100.2uA
1.8V      0A         0A         15.76uA
[Ramp]
| variable   typ   min   max
dV/dt_r   0.368/0.163n   0.319/0.195n   0.432/0.140n
dV/dt_f   0.369/0.149n   0.323/0.172n   0.432/0.133n
R_load = 50.000
[Rising Waveform]
R_fixture= 50.000
V_fixture= 0.0
V_fixture_min= 0.0
V_fixture_max= 0.0
|time   V(typ)   V(min)   V(max)
0s        816.5nV    7.287uV    250.2nV
441ps     -170.6uV   -60.34uV   14.33mV
479ps     -1.911mV   24.22uV    92.83mV
558ps     22.48mV    -1.158mV   426.2mV
653ps     289.7mV    6.258mV    600.5mV
753ps     479.9mV    170mV      659.6mV
828ps     538.4mV    323.3mV    684mV
898ps     564.3mV    408.5mV    697.9mV
1.238ns   607.6mV    515mV      718mV
50ns      613.9mV    532.4mV    720.7mV
[Rising Waveform]
R_fixture= 50.000
V_fixture= 1.800
V_fixture_min= 1.750
V_fixture_max= 1.850
|time   V(typ)   V(min)   V(max)
0s        1.184V     1.212V     1.13V
423ps     1.185V     1.212V     1.144V
456ps     1.184V     1.212V     1.216V
538ps     1.218V     1.211V     1.595V
613ps     1.489V     1.219V     1.725V
698ps     1.664V     1.386V     1.793V
752ps     1.715V     1.531V     1.813V
822ps     1.752V     1.632V     1.829V
1.165ns   1.795V     1.739V     1.847V
50ns      1.8V       1.75V      1.85V
[Falling Waveform]
R_fixture= 50.000
V_fixture= 1.800
V_fixture_min= 1.750
V_fixture_max= 1.850
|time   V(typ)   V(min)   V(max)
0s        1.8V       1.75V      1.85V
448ps     1.8V       1.75V      1.829V
508ps     1.8V       1.75V      1.725V
562ps     1.773V     1.751V     1.49V
638ps     1.623V     1.744V     1.285V
711ps     1.393V     1.687V     1.215V
808ps     1.273V     1.467V     1.177V
958ps     1.219V     1.287V     1.148V
1.285ns   1.189V     1.225V     1.133V
50ns      1.184V     1.212V     1.13V
[Falling Waveform]
R_fixture= 50.000
V_fixture= 0.0
V_fixture_min= 0.0
V_fixture_max= 0.0
|time   V(typ)   V(min)   V(max)
0s        613.9mV    532.4mV    720.7mV
432ps     614mV      532.3mV    705.9mV
485ps     614.8mV    532.4mV    610.3mV
554ps     581.2mV    533.2mV    302.8mV
629ps     370.8mV    522.7mV    144.3mV
701ps     175.5mV    436.3mV    80.52mV
777ps     94.71mV    230.9mV    40.98mV
837ps     58.19mV    134.7mV    23.26mV
1.111ns   5.3mV      15.22mV    1.819mV
50ns      2.784uV    8.325uV    1.684uV
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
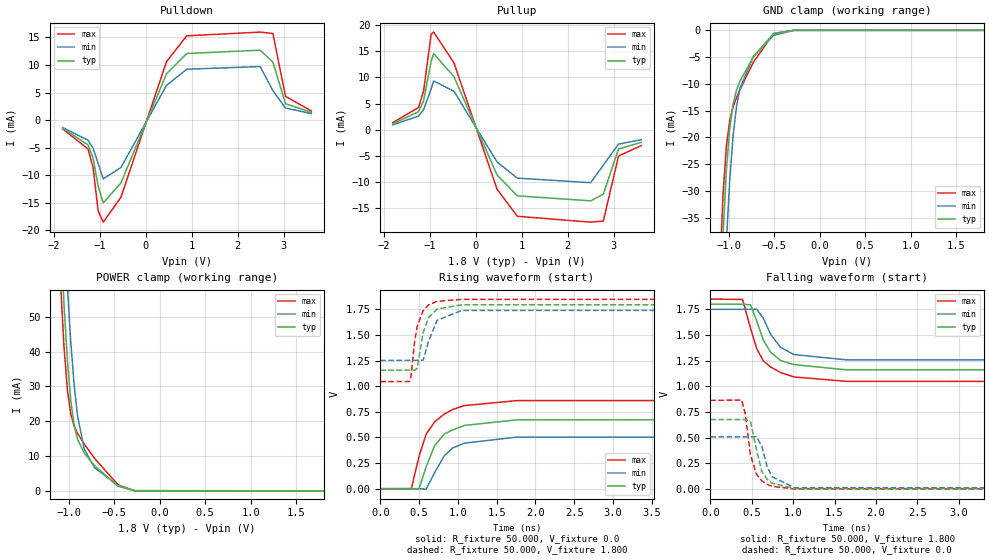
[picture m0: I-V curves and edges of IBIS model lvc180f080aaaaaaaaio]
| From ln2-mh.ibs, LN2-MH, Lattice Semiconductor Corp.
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|   Model lvc180f080aaaaaaaaio
[Model] lvc180f080aaaaaaaaio
Model_type I/O
Polarity   Non-Inverting
Enable   Active-Low
Vinl =  0.630V
Vinh =  1.170V
Vmeas =  0.900V
Cref =  0.0F
Rref =  1.000M
Vref =  0.0V
C_comp   2.000pF   1.500pF   2.500pF
[Temperature Range]   25.000   0.125k   -40.000
[Voltage Range]   1.800V   1.750V   1.850V
[C Comp Corner]
C_comp   2.000pF   1.500pF   2.500pF
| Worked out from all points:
|   slope of the pulldown table from 0 to 0.27 V, typ, clamps not added: 50.5 ohm
|   slope of the pullup table from 0 to 0.27 V, typ, clamps not added: 50.1 ohm
|   GND clamp passes 1 mA (typ) near -0.54 V on its own axis
|   POWER clamp passes 1 mA (typ) near -0.43 V on its own axis
|   rising waveform, R_fixture 50.000, V_fixture 0.0: 20-80 % time 285ps typ, 284ps min, 301ps max; typ from 0 V to 0.677 V
|   rising waveform, R_fixture 50.000, V_fixture 1.800: 20-80 % time 121ps typ, 141ps min, 108ps max; typ from 1.16 V to 1.8 V
|   falling waveform, R_fixture 50.000, V_fixture 1.800: 20-80 % time 239ps typ, 250ps min, 244ps max; typ from 1.8 V to 1.16 V
|   falling waveform, R_fixture 50.000, V_fixture 0.0: 20-80 % time 122ps typ, 140ps min, 109ps max; typ from 0.678 V to 0 V
[Pulldown]
|Voltage   I(typ)   I(min)   I(max)
-1.8V     -1.467mA   -1.347mA   -1.594mA
-1.25V    -4.498mA   -3.644mA   -5.247mA
-1.14V    -6.904mA   -5.12mA    -8.606mA
-1.03V    -11.99mA   -7.86mA    -16.51mA
-920mV    -15.03mA   -10.67mA   -18.53mA
-535mV    -11.38mA   -8.605mA   -14mA
455mV     8.405mA    6.312mA    10.62mA
895mV     12.1mA     9.244mA    15.31mA
2.49V     12.69mA    9.719mA    15.98mA
2.765V    10.53mA    5.338mA    15.72mA
3.04V     2.979mA    2.201mA    4.31mA
3.6V      1.405mA    1.18mA     1.674mA
[Pullup]
|Voltage   I(typ)   I(min)   I(max)
-1.8V     1.12mA     921.8uA    1.36mA
-1.24V    3.446mA    2.621mA    4.254mA
-1.13V    5.497mA    3.817mA    7.346mA
-965mV    13.12mA    7.785mA    18.26mA
-910mV    14.56mA    9.33mA     18.67mA
-470mV    10.14mA    7.355mA    12.79mA
465mV     -8.626mA   -6.147mA   -11.34mA
905mV     -12.63mA   -9.245mA   -16.53mA
2.5V      -13.59mA   -10.12mA   -17.67mA
2.775V    -12.3mA    -6.757mA   -17.44mA
3.105V    -3.679mA   -2.753mA   -5.021mA
3.6V      -2.406mA   -1.897mA   -3.021mA
[GND_clamp]
|Voltage   I(typ)   I(min)   I(max)
-1.8V     -585.7mA   -591.6mA   -585.2mA
-1.097V   -54.7mA    -72.3mA    -45.44mA
-1.06V    -38.22mA   -54.4mA    -30.73mA
-1.023V   -26.04mA   -39.44mA   -21.56mA
-986mV    -18.22mA   -27.85mA   -16.81mA
-949mV    -13.75mA   -19.63mA   -14.29mA
-912mV    -11.19mA   -14.24mA   -12.58mA
-875mV    -9.506mA   -10.84mA   -11.12mA
-727mV    -4.941mA   -4.928mA   -5.958mA
-505mV    -576.1uA   -916.7uA   -589.6uA
-283mV    -824.2nA   -10.84uA   -168.9nA
1.8V      0A         0A         0A
[POWER_clamp]
|Voltage   I(typ)   I(min)   I(max)
-1.789V   650.9mA    666.7mA    643.9mA
-1.086V   73.37mA    99.35mA    59.09mA
-1.049V   53.37mA    77.75mA    41.19mA
-1.012V   37.31mA    58.71mA    28.94mA
-975mV    25.9mA     42.77mA    22.1mA
-938mV    18.85mA    30.42mA    18.6mA
-901mV    14.84mA    21.56mA    16.51mA
-827mV    10.86mA    11.99mA    13.46mA
-716mV    7.305mA    6.728mA    9.397mA
-457mV    1.344mA    1.526mA    1.755mA
-272mV    20.87uA    98.79uA    12.36uA
1.8V      0A         0A         0A
[Ramp]
| variable   typ   min   max
dV/dt_r   0.406/0.284n   0.306/0.283n   0.519/0.301n
dV/dt_f   0.386/0.238n   0.299/0.250n   0.483/0.244n
R_load = 50.000
[Rising Waveform]
R_fixture= 50.000
V_fixture= 0.0
V_fixture_min= 0.0
V_fixture_max= 0.0
|time   V(typ)   V(min)   V(max)
0s        848.9nV    8.122uV    251.1nV
400ps     24.73uV    -104.9uV   985.9uV
500ps     432.7uV    151.5uV    316.6mV
591ps     215mV      -4.466mV   533mV
701ps     420mV      157.6mV    652.5mV
824ps     531.7mV    320.6mV    727.9mV
934ps     574.8mV    398.2mV    772.6mV
1.085ns   617.2mV    444.6mV    810.7mV
1.762ns   671.8mV    503.6mV    859.6mV
50ns      677.3mV    509.2mV    864.7mV
[Rising Waveform]
R_fixture= 50.000
V_fixture= 1.800
V_fixture_min= 1.750
V_fixture_max= 1.850
|time   V(typ)   V(min)   V(max)
0s        1.156V     1.252V     1.045V
376ps     1.157V     1.252V     1.046V
395ps     1.158V     1.252V     1.094V
441ps     1.156V     1.253V     1.426V
475ps     1.172V     1.253V     1.582V
552ps     1.521V     1.253V     1.737V
623ps     1.67V      1.44V      1.794V
732ps     1.752V     1.643V     1.828V
1.052ns   1.794V     1.739V     1.847V
50ns      1.8V       1.75V      1.85V
[Falling Waveform]
R_fixture= 50.000
V_fixture= 1.800
V_fixture_min= 1.750
V_fixture_max= 1.850
|time   V(typ)   V(min)   V(max)
0s        1.8V       1.75V      1.85V
390ps     1.8V       1.75V      1.846V
486ps     1.794V     1.75V      1.567V
560ps     1.639V     1.751V     1.369V
640ps     1.451V     1.665V     1.25V
730ps     1.331V     1.505V     1.188V
850ps     1.252V     1.38V      1.135V
1.01ns    1.212V     1.31V      1.092V
1.651ns   1.161V     1.258V     1.049V
50ns      1.157V     1.252V     1.045V
[Falling Waveform]
R_fixture= 50.000
V_fixture= 0.0
V_fixture_min= 0.0
V_fixture_max= 0.0
|time   V(typ)   V(min)   V(max)
0s        677.5mV    509.3mV    864.9mV
378ps     677.4mV    509.2mV    866.2mV
422ps     677.4mV    509.1mV    737.7mV
484ps     663.1mV    508.9mV    339.9mV
557ps     385.4mV    510.6mV    145.5mV
623ps     171.5mV    416.4mV    82.01mV
687ps     96.11mV    219.3mV    47.05mV
747ps     58.15mV    120.6mV    27.07mV
1.017ns   5.987mV    14.61mV    2.366mV
50ns      2.827uV    9.139uV    1.598uV
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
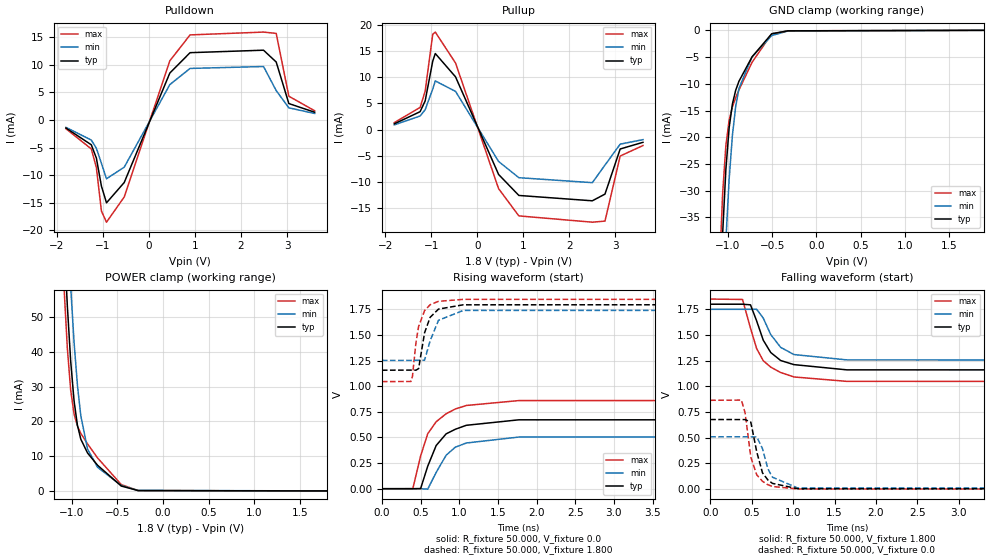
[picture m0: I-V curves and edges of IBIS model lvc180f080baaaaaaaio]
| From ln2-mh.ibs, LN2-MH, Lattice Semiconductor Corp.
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|   Model lvc180f080baaaaaaaio
[Model] lvc180f080baaaaaaaio
Model_type I/O
Polarity   Non-Inverting
Enable   Active-Low
Vinl =  0.630V
Vinh =  1.170V
Vmeas =  0.900V
Cref =  0.0F
Rref =  1.000M
Vref =  0.0V
C_comp   2.000pF   1.500pF   2.500pF
[Temperature Range]   25.000   0.125k   -40.000
[Voltage Range]   1.800V   1.750V   1.850V
[C Comp Corner]
C_comp   2.000pF   1.500pF   2.500pF
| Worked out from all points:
|   slope of the pulldown table from 0 to 0.27 V, typ, clamps not added: 50.5 ohm
|   slope of the pullup table from 0 to 0.27 V, typ, clamps not added: 50.7 ohm
|   GND clamp passes 1 mA (typ) near -0.54 V on its own axis
|   POWER clamp passes 1 mA (typ) near -0.43 V on its own axis
|   rising waveform, R_fixture 50.000, V_fixture 0.0: 20-80 % time 285ps typ, 284ps min, 301ps max; typ from 0 V to 0.677 V
|   rising waveform, R_fixture 50.000, V_fixture 1.800: 20-80 % time 121ps typ, 141ps min, 108ps max; typ from 1.16 V to 1.8 V
|   falling waveform, R_fixture 50.000, V_fixture 1.800: 20-80 % time 239ps typ, 250ps min, 244ps max; typ from 1.8 V to 1.16 V
|   falling waveform, R_fixture 50.000, V_fixture 0.0: 20-80 % time 122ps typ, 140ps min, 110ps max; typ from 0.678 V to 0 V
[Pulldown]
|Voltage   I(typ)   I(min)   I(max)
-1.8V     -1.465mA   -1.345mA   -1.593mA
-1.25V    -4.494mA   -3.641mA   -5.244mA
-1.14V    -6.9mA     -5.114mA   -8.602mA
-1.03V    -11.98mA   -7.852mA   -16.5mA
-920mV    -15.01mA   -10.65mA   -18.52mA
-535mV    -11.33mA   -8.557mA   -13.95mA
455mV     8.497mA    6.404mA    10.71mA
895mV     12.19mA    9.336mA    15.41mA
2.49V     12.64mA    9.682mA    15.92mA
2.765V    10.5mA     5.321mA    15.68mA
3.04V     2.971mA    2.194mA    4.299mA
3.6V      1.402mA    1.177mA    1.669mA
[Pullup]
|Voltage   I(typ)   I(min)   I(max)
-1.8V     1.116mA    918.1uA    1.356mA
-1.24V    3.438mA    2.613mA    4.245mA
-1.13V    5.485mA    3.806mA    7.332mA
-965mV    13.09mA    7.764mA    18.22mA
-910mV    14.53mA    9.303mA    18.62mA
-470mV    10.08mA    7.307mA    12.72mA
465mV     -8.538mA   -6.064mA   -11.25mA
905mV     -12.54mA   -9.153mA   -16.44mA
2.5V      -13.56mA   -10.1mA    -17.64mA
2.775V    -12.28mA   -6.748mA   -17.43mA
3.105V    -3.676mA   -2.75mA    -5.019mA
3.6V      -2.404mA   -1.895mA   -3.019mA
[GND_clamp]
|Voltage   I(typ)   I(min)   I(max)
-1.8V     -585.7mA   -591.6mA   -585.2mA
-1.097V   -54.7mA    -72.3mA    -45.45mA
-1.06V    -38.22mA   -54.4mA    -30.73mA
-1.023V   -26.05mA   -39.45mA   -21.57mA
-986mV    -18.23mA   -27.86mA   -16.82mA
-949mV    -13.77mA   -19.64mA   -14.3mA
-912mV    -11.21mA   -14.25mA   -12.59mA
-875mV    -9.522mA   -10.86mA   -11.14mA
-727mV    -4.965mA   -4.953mA   -5.98mA
-505mV    -637.4uA   -970.8uA   -651.9uA
-320mV    -95.22uA   -117.2uA   -94.14uA
1.89V     0A         0A         0A
[POWER_clamp]
|Voltage   I(typ)   I(min)   I(max)
-1.789V   650.9mA    666.7mA    643.9mA
-1.086V   73.39mA    99.36mA    59.11mA
-1.049V   53.39mA    77.76mA    41.22mA
-1.012V   37.33mA    58.73mA    28.98mA
-975mV    25.93mA    42.79mA    22.14mA
-938mV    18.88mA    30.44mA    18.64mA
-901mV    14.88mA    21.59mA    16.55mA
-827mV    10.9mA     12.03mA    13.51mA
-716mV    7.349mA    6.765mA    9.446mA
-457mV    1.407mA    1.575mA    1.826mA
-272mV    92.84uA    154.8uA    100.2uA
1.8V      0A         0A         0A
[Ramp]
| variable   typ   min   max
dV/dt_r   0.406/0.284n   0.306/0.282n   0.519/0.301n
dV/dt_f   0.386/0.240n   0.299/0.250n   0.483/0.244n
R_load = 50.000
[Rising Waveform]
R_fixture= 50.000
V_fixture= 0.0
V_fixture_min= 0.0
V_fixture_max= 0.0
|time   V(typ)   V(min)   V(max)
0s        848.9nV    8.122uV    251.1nV
400ps     24.79uV    -104.8uV   891.7uV
501ps     1.465mV    157.3uV    319.7mV
593ps     220mV      -4.389mV   536.4mV
702ps     421.4mV    159.2mV    653.2mV
831ps     535.3mV    327mV      731.3mV
950ps     580.3mV    405.6mV    777.7mV
1.092ns   618.7mV    446mV      812mV
1.768ns   671.9mV    503.7mV    859.7mV
50ns      677.3mV    509.2mV    864.8mV
[Rising Waveform]
R_fixture= 50.000
V_fixture= 1.800
V_fixture_min= 1.750
V_fixture_max= 1.850
|time   V(typ)   V(min)   V(max)
0s        1.156V     1.252V     1.045V
376ps     1.157V     1.252V     1.046V
395ps     1.158V     1.252V     1.094V
441ps     1.156V     1.253V     1.426V
475ps     1.172V     1.253V     1.582V
552ps     1.521V     1.253V     1.737V
624ps     1.672V     1.443V     1.795V
732ps     1.752V     1.643V     1.828V
1.052ns   1.794V     1.739V     1.847V
50ns      1.8V       1.75V      1.85V
[Falling Waveform]
R_fixture= 50.000
V_fixture= 1.800
V_fixture_min= 1.750
V_fixture_max= 1.850
|time   V(typ)   V(min)   V(max)
0s        1.8V       1.75V      1.85V
390ps     1.8V       1.75V      1.846V
486ps     1.794V     1.75V      1.567V
560ps     1.638V     1.751V     1.369V
640ps     1.45V      1.665V     1.25V
730ps     1.33V      1.505V     1.188V
850ps     1.252V     1.38V      1.135V
1.01ns    1.212V     1.31V      1.092V
1.65ns    1.161V     1.258V     1.049V
50ns      1.156V     1.252V     1.045V
[Falling Waveform]
R_fixture= 50.000
V_fixture= 0.0
V_fixture_min= 0.0
V_fixture_max= 0.0
|time   V(typ)   V(min)   V(max)
0s        677.5mV    509.3mV    864.9mV
377ps     677.4mV    509.2mV    866.7mV
421ps     677.3mV    509.1mV    742.3mV
490ps     652.7mV    508.9mV    311.3mV
562ps     361.5mV    508.8mV    138.8mV
631ps     158.7mV    394.1mV    76.62mV
697ps     88.56mV    196.1mV    42.9mV
751ps     56.28mV    116.6mV    26.07mV
1.056ns   4.365mV    10.9mV     1.687mV
50ns      2.938uV    9.139uV    1.65uV
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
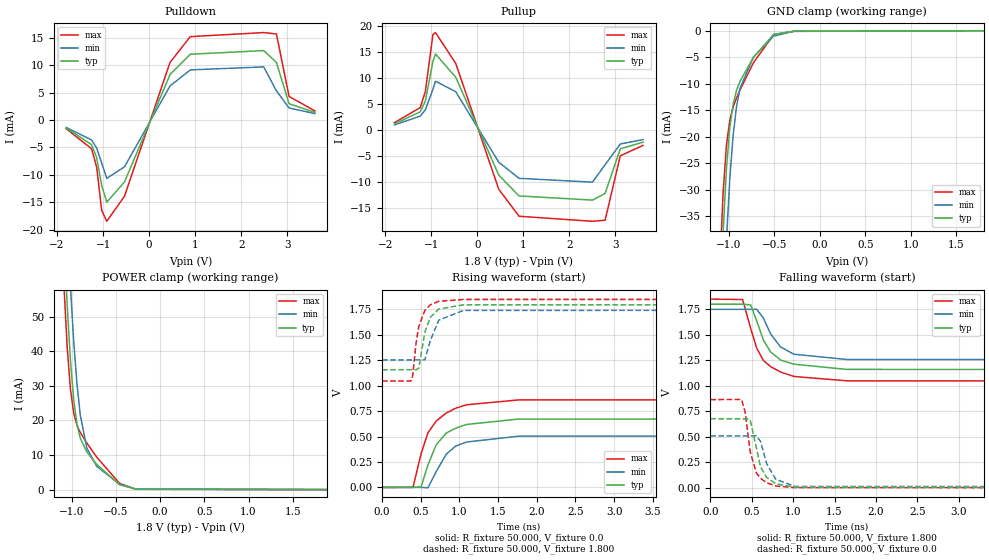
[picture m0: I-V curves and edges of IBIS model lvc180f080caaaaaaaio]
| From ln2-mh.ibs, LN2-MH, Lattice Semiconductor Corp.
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|   Model lvc180f080caaaaaaaio
[Model] lvc180f080caaaaaaaio
Model_type I/O
Polarity   Non-Inverting
Enable   Active-Low
Vinl =  0.630V
Vinh =  1.170V
Vmeas =  0.900V
Cref =  0.0F
Rref =  1.000M
Vref =  0.0V
C_comp   2.000pF   1.500pF   2.500pF
[Temperature Range]   25.000   0.125k   -40.000
[Voltage Range]   1.800V   1.750V   1.850V
[C Comp Corner]
C_comp   2.000pF   1.500pF   2.500pF
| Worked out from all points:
|   slope of the pulldown table from 0 to 0.27 V, typ, clamps not added: 51.1 ohm
|   slope of the pullup table from 0 to 0.27 V, typ, clamps not added: 50.1 ohm
|   GND clamp passes 1 mA (typ) near -0.53 V on its own axis
|   POWER clamp passes 1 mA (typ) near -0.43 V on its own axis
|   rising waveform, R_fixture 50.000, V_fixture 0.0: 20-80 % time 285ps typ, 284ps min, 301ps max; typ from 0 V to 0.677 V
|   rising waveform, R_fixture 50.000, V_fixture 1.800: 20-80 % time 121ps typ, 141ps min, 108ps max; typ from 1.16 V to 1.8 V
|   falling waveform, R_fixture 50.000, V_fixture 1.800: 20-80 % time 239ps typ, 250ps min, 244ps max; typ from 1.8 V to 1.16 V
|   falling waveform, R_fixture 50.000, V_fixture 0.0: 20-80 % time 122ps typ, 141ps min, 110ps max; typ from 0.678 V to 0 V
[Pulldown]
|Voltage   I(typ)   I(min)   I(max)
-1.8V     -1.459mA   -1.34mA    -1.585mA
-1.25V    -4.484mA   -3.631mA   -5.231mA
-1.14V    -6.884mA   -5.102mA   -8.582mA
-1.03V    -11.95mA   -7.834mA   -16.46mA
-920mV    -14.98mA   -10.63mA   -18.47mA
-535mV    -11.29mA   -8.535mA   -13.89mA
455mV     8.318mA    6.228mA    10.53mA
895mV     12.01mA    9.153mA    15.22mA
2.49V     12.67mA    9.698mA    15.96mA
2.765V    10.52mA    5.331mA    15.71mA
3.04V     2.976mA    2.198mA    4.308mA
3.6V      1.404mA    1.179mA    1.673mA
[Pullup]
|Voltage   I(typ)   I(min)   I(max)
-1.8V     1.119mA    920.4uA    1.359mA
-1.24V    3.443mA    2.618mA    4.252mA
-1.13V    5.493mA    3.812mA    7.343mA
-965mV    13.11mA    7.776mA    18.25mA
-910mV    14.55mA    9.318mA    18.66mA
-470mV    10.09mA    7.312mA    12.75mA
465mV     -8.717mA   -6.238mA   -11.44mA
905mV     -12.72mA   -9.335mA   -16.62mA
2.5V      -13.52mA   -10.07mA   -17.59mA
2.775V    -12.25mA   -6.73mA    -17.38mA
3.105V    -3.667mA   -2.742mA   -5.006mA
3.6V      -2.398mA   -1.89mA    -3.012mA
[GND_clamp]
|Voltage   I(typ)   I(min)   I(max)
-1.8V     -585.7mA   -591.6mA   -585.2mA
-1.097V   -54.72mA   -72.32mA   -45.47mA
-1.06V    -38.25mA   -54.42mA   -30.77mA
-1.023V   -26.08mA   -39.47mA   -21.61mA
-986mV    -18.26mA   -27.88mA   -16.87mA
-949mV    -13.8mA    -19.67mA   -14.35mA
-912mV    -11.24mA   -14.28mA   -12.64mA
-875mV    -9.559mA   -10.89mA   -11.19mA
-727mV    -5.003mA   -4.98mA    -6.032mA
-505mV    -676uA     -991.2uA   -711.7uA
-283mV    -81.53uA   -80.08uA   -96.55uA
1.8V      0A         0A         0A
[POWER_clamp]
|Voltage   I(typ)   I(min)   I(max)
-1.789V   650.9mA    666.7mA    643.9mA
-1.086V   73.38mA    99.35mA    59.1mA
-1.049V   53.37mA    77.75mA    41.2mA
-1.012V   37.32mA    58.72mA    28.95mA
-975mV    25.91mA    42.78mA    22.11mA
-938mV    18.86mA    30.43mA    18.61mA
-901mV    14.86mA    21.58mA    16.52mA
-827mV    10.88mA    12.01mA    13.47mA
-716mV    7.324mA    6.749mA    9.413mA
-457mV    1.39mA     1.571mA    1.797mA
-272mV    110.1uA    181.7uA    102.9uA
1.89V     0A         0A         0A
[Ramp]
| variable   typ   min   max
dV/dt_r   0.406/0.284n   0.306/0.283n   0.519/0.301n
dV/dt_f   0.386/0.240n   0.299/0.250n   0.483/0.244n
R_load = 50.000
[Rising Waveform]
R_fixture= 50.000
V_fixture= 0.0
V_fixture_min= 0.0
V_fixture_max= 0.0
|time   V(typ)   V(min)   V(max)
0s        848.9nV    8.122uV    251.1nV
400ps     24.1uV     -104.8uV   891.7uV
505ps     6.085mV    152.6uV    331.8mV
593ps     219.8mV    -4.397mV   536.4mV
700ps     418.6mV    155.7mV    651.8mV
830ps     534.8mV    326.1mV    730.8mV
950ps     580.3mV    405.6mV    777.7mV
1.091ns   618.5mV    445.8mV    811.8mV
1.768ns   671.9mV    503.7mV    859.7mV
50ns      677.3mV    509.2mV    864.8mV
[Rising Waveform]
R_fixture= 50.000
V_fixture= 1.800
V_fixture_min= 1.750
V_fixture_max= 1.850
|time   V(typ)   V(min)   V(max)
0s        1.156V     1.252V     1.045V
376ps     1.157V     1.252V     1.046V
395ps     1.158V     1.252V     1.094V
441ps     1.156V     1.253V     1.426V
475ps     1.172V     1.253V     1.582V
552ps     1.521V     1.253V     1.737V
623ps     1.67V      1.44V      1.794V
732ps     1.752V     1.643V     1.828V
1.052ns   1.794V     1.739V     1.847V
50ns      1.8V       1.75V      1.85V
[Falling Waveform]
R_fixture= 50.000
V_fixture= 1.800
V_fixture_min= 1.750
V_fixture_max= 1.850
|time   V(typ)   V(min)   V(max)
0s        1.8V       1.75V      1.85V
390ps     1.8V       1.75V      1.846V
486ps     1.794V     1.75V      1.567V
560ps     1.638V     1.751V     1.369V
640ps     1.45V      1.665V     1.25V
729ps     1.331V     1.507V     1.188V
850ps     1.252V     1.38V      1.135V
1.01ns    1.212V     1.31V      1.092V
1.65ns    1.161V     1.258V     1.049V
50ns      1.157V     1.252V     1.045V
[Falling Waveform]
R_fixture= 50.000
V_fixture= 0.0
V_fixture_min= 0.0
V_fixture_max= 0.0
|time   V(typ)   V(min)   V(max)
0s        677.5mV    509.3mV    864.9mV
377ps     677.4mV    509.2mV    866.7mV
421ps     677.3mV    509.1mV    742.3mV
481ps     667.5mV    508.9mV    354.3mV
556ps     391.5mV    510.6mV    146.7mV
606ps     206.7mV    455.5mV    94.3mV
680ps     102.1mV    237.8mV    50.08mV
790ps     40.38mV    84.48mV    18.17mV
1.02ns    5.849mV    14.29mV    2.304mV
50ns      2.938uV    9.21uV     1.65uV
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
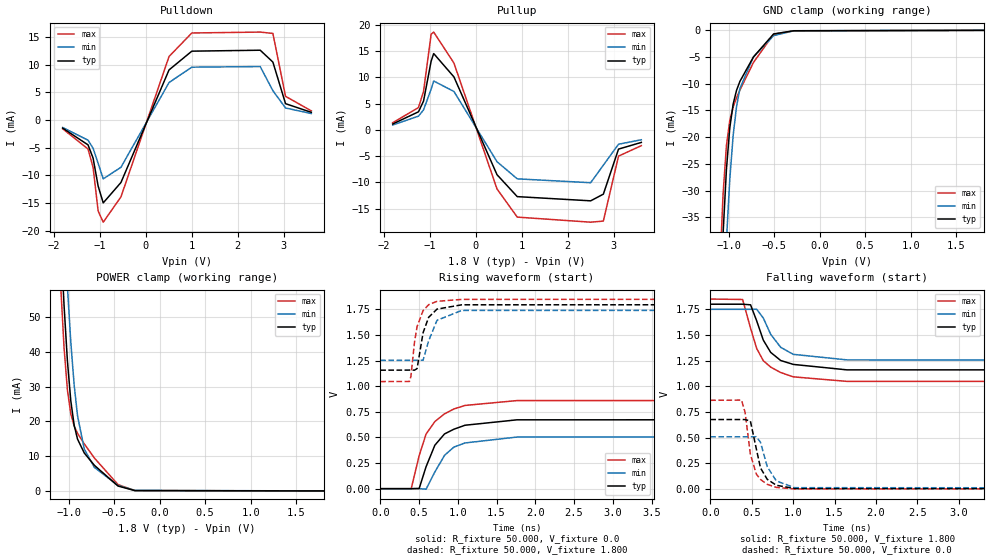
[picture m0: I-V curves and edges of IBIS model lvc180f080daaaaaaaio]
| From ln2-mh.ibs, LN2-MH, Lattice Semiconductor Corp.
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|   Model lvc180f080daaaaaaaio
[Model] lvc180f080daaaaaaaio
Model_type I/O
Polarity   Non-Inverting
Enable   Active-Low
Vinl =  0.630V
Vinh =  1.170V
Vmeas =  0.900V
Cref =  0.0F
Rref =  1.000M
Vref =  0.0V
C_comp   2.000pF   1.500pF   2.500pF
[Temperature Range]   25.000   0.125k   -40.000
[Voltage Range]   1.800V   1.750V   1.850V
[C Comp Corner]
C_comp   2.000pF   1.500pF   2.500pF
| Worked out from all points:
|   slope of the pulldown table from 0 to 0.27 V, typ, clamps not added: 51.1 ohm
|   slope of the pullup table from 0 to 0.27 V, typ, clamps not added: 50.7 ohm
|   GND clamp passes 1 mA (typ) near -0.53 V on its own axis
|   POWER clamp passes 1 mA (typ) near -0.43 V on its own axis
|   rising waveform, R_fixture 50.000, V_fixture 0.0: 20-80 % time 285ps typ, 284ps min, 301ps max; typ from 0 V to 0.677 V
|   rising waveform, R_fixture 50.000, V_fixture 1.800: 20-80 % time 121ps typ, 141ps min, 108ps max; typ from 1.16 V to 1.8 V
|   falling waveform, R_fixture 50.000, V_fixture 1.800: 20-80 % time 239ps typ, 250ps min, 244ps max; typ from 1.8 V to 1.16 V
|   falling waveform, R_fixture 50.000, V_fixture 0.0: 20-80 % time 122ps typ, 141ps min, 110ps max; typ from 0.678 V to 0 V
[Pulldown]
|Voltage   I(typ)   I(min)   I(max)
-1.8V     -1.459mA   -1.34mA    -1.585mA
-1.25V    -4.484mA   -3.631mA   -5.231mA
-1.14V    -6.884mA   -5.102mA   -8.582mA
-1.03V    -11.95mA   -7.834mA   -16.46mA
-920mV    -14.98mA   -10.63mA   -18.47mA
-535mV    -11.29mA   -8.535mA   -13.89mA
510mV     9.082mA    6.802mA    11.51mA
1.005V    12.47mA    9.575mA    15.76mA
2.49V     12.64mA    9.682mA    15.92mA
2.765V    10.5mA     5.321mA    15.68mA
3.04V     2.971mA    2.194mA    4.299mA
3.6V      1.402mA    1.177mA    1.669mA
[Pullup]
|Voltage   I(typ)   I(min)   I(max)
-1.8V     1.116mA    918.1uA    1.356mA
-1.24V    3.438mA    2.613mA    4.245mA
-1.13V    5.485mA    3.806mA    7.332mA
-965mV    13.09mA    7.764mA    18.22mA
-910mV    14.53mA    9.303mA    18.62mA
-470mV    10.08mA    7.307mA    12.72mA
465mV     -8.538mA   -6.064mA   -11.25mA
905mV     -12.72mA   -9.335mA   -16.62mA
2.5V      -13.52mA   -10.07mA   -17.59mA
2.775V    -12.25mA   -6.73mA    -17.38mA
3.105V    -3.667mA   -2.742mA   -5.006mA
3.6V      -2.398mA   -1.89mA    -3.012mA
[GND_clamp]
|Voltage   I(typ)   I(min)   I(max)
-1.8V     -585.7mA   -591.6mA   -585.2mA
-1.097V   -54.72mA   -72.32mA   -45.47mA
-1.06V    -38.25mA   -54.42mA   -30.77mA
-1.023V   -26.08mA   -39.47mA   -21.61mA
-986mV    -18.26mA   -27.88mA   -16.87mA
-949mV    -13.8mA    -19.67mA   -14.35mA
-912mV    -11.24mA   -14.28mA   -12.64mA
-875mV    -9.559mA   -10.89mA   -11.19mA
-727mV    -5.003mA   -4.98mA    -6.032mA
-505mV    -676uA     -991.2uA   -711.7uA
-283mV    -81.53uA   -80.08uA   -96.55uA
1.8V      -11.32nA   0A         -15.28uA
[POWER_clamp]
|Voltage   I(typ)   I(min)   I(max)
-1.789V   650.9mA    666.7mA    643.9mA
-1.086V   73.39mA    99.36mA    59.11mA
-1.049V   53.39mA    77.76mA    41.22mA
-1.012V   37.33mA    58.73mA    28.98mA
-975mV    25.93mA    42.79mA    22.14mA
-938mV    18.88mA    30.44mA    18.64mA
-901mV    14.88mA    21.59mA    16.55mA
-827mV    10.9mA     12.03mA    13.51mA
-716mV    7.349mA    6.765mA    9.446mA
-457mV    1.407mA    1.575mA    1.826mA
-272mV    92.84uA    154.8uA    100.2uA
1.8V      0A         0A         15.76uA
[Ramp]
| variable   typ   min   max
dV/dt_r   0.407/0.284n   0.306/0.282n   0.519/0.301n
dV/dt_f   0.386/0.240n   0.299/0.250n   0.483/0.244n
R_load = 50.000
[Rising Waveform]
R_fixture= 50.000
V_fixture= 0.0
V_fixture_min= 0.0
V_fixture_max= 0.0
|time   V(typ)   V(min)   V(max)
0s        848.9nV    8.122uV    251.1nV
399ps     20.03uV    -104.8uV   44.99uV
502ps     2.505mV    156.1uV    323.4mV
591ps     214.9mV    -4.746mV   533.3mV
704ps     424mV      163mV      654.7mV
829ps     534.2mV    325.4mV    730.4mV
949ps     580mV      405.3mV    777.4mV
1.093ns   618.9mV    446.2mV    812.2mV
1.764ns   671.8mV    503.7mV    859.5mV
50ns      677.3mV    509.2mV    864.6mV
[Rising Waveform]
R_fixture= 50.000
V_fixture= 1.800
V_fixture_min= 1.750
V_fixture_max= 1.850
|time   V(typ)   V(min)   V(max)
0s        1.156V     1.252V     1.045V
376ps     1.157V     1.252V     1.046V
395ps     1.158V     1.252V     1.094V
441ps     1.156V     1.253V     1.426V
475ps     1.172V     1.253V     1.582V
552ps     1.521V     1.253V     1.737V
624ps     1.672V     1.443V     1.795V
732ps     1.752V     1.643V     1.828V
1.052ns   1.794V     1.739V     1.847V
50ns      1.8V       1.75V      1.85V
[Falling Waveform]
R_fixture= 50.000
V_fixture= 1.800
V_fixture_min= 1.750
V_fixture_max= 1.850
|time   V(typ)   V(min)   V(max)
0s        1.8V       1.75V      1.85V
390ps     1.8V       1.75V      1.846V
486ps     1.794V     1.75V      1.567V
560ps     1.638V     1.751V     1.369V
640ps     1.45V      1.665V     1.25V
729ps     1.331V     1.507V     1.188V
850ps     1.252V     1.38V      1.135V
1.002ns   1.214V     1.312V     1.093V
1.65ns    1.161V     1.258V     1.049V
50ns      1.157V     1.252V     1.045V
[Falling Waveform]
R_fixture= 50.000
V_fixture= 0.0
V_fixture_min= 0.0
V_fixture_max= 0.0
|time   V(typ)   V(min)   V(max)
0s        677.5mV    509.3mV    864.9mV
377ps     677.4mV    509.2mV    866.7mV
420ps     677.3mV    509.1mV    747.3mV
484ps     663.1mV    508.9mV    338.7mV
556ps     391.1mV    510.7mV    146.7mV
606ps     206.4mV    455.8mV    94.3mV
687ps     96.22mV    219.5mV    46.99mV
797ps     38.02mV    79.92mV    17.02mV
1.018ns   5.945mV    14.5mV     2.344mV
50ns      2.779uV    9.209uV    1.65uV
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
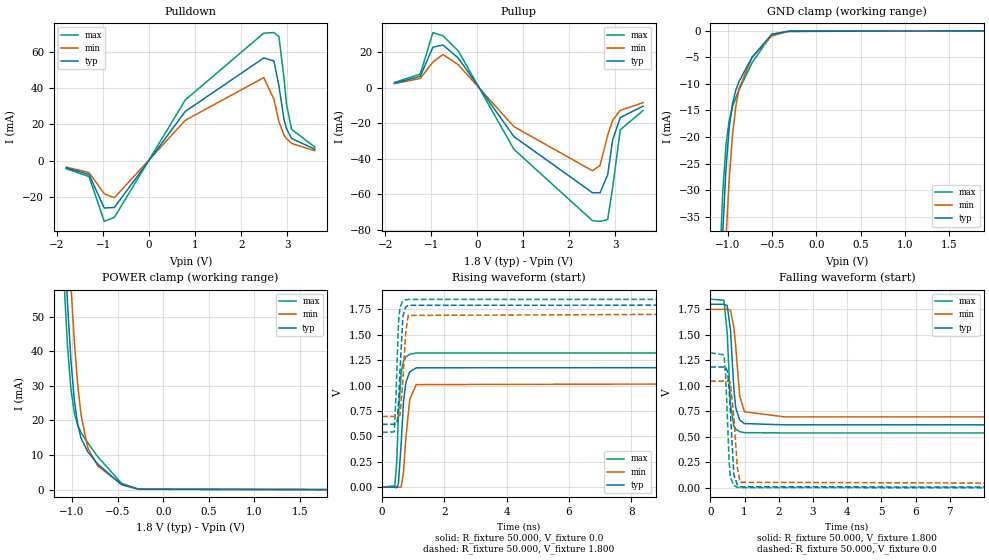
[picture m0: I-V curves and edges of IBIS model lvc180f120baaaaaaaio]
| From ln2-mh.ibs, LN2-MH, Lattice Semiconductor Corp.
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|   Model lvc180f120baaaaaaaio
[Model] lvc180f120baaaaaaaio
Model_type I/O
Polarity   Non-Inverting
Enable   Active-Low
Vinl =  0.630V
Vinh =  1.170V
Vmeas =  0.900V
Cref =  0.0F
Rref =  1.000M
Vref =  0.0V
C_comp   2.000pF   1.500pF   2.500pF
[Temperature Range]   25.000   0.125k   -40.000
[Voltage Range]   1.800V   1.750V   1.850V
[C Comp Corner]
C_comp   2.000pF   1.500pF   2.500pF
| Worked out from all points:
|   slope of the pulldown table from 0 to 0.27 V, typ, clamps not added: 25.5 ohm
|   slope of the pullup table from 0 to 0.27 V, typ, clamps not added: 25.6 ohm
|   GND clamp passes 1 mA (typ) near -0.54 V on its own axis
|   POWER clamp passes 1 mA (typ) near -0.43 V on its own axis
|   rising waveform, R_fixture 50.000, V_fixture 0.0: 20-80 % time 140ps typ, 168ps min, 115ps max; typ from 0 V to 1.19 V
|   rising waveform, R_fixture 50.000, V_fixture 1.800: 20-80 % time 105ps typ, 127ps min, 88.2ps max; typ from 0.618 V to 1.8 V
|   falling waveform, R_fixture 50.000, V_fixture 1.800: 20-80 % time 132ps typ, 156ps min, 114ps max; typ from 1.8 V to 0.618 V
|   falling waveform, R_fixture 50.000, V_fixture 0.0: 20-80 % time 108ps typ, 128ps min, 94.4ps max; typ from 1.19 V to 0 V
[Pulldown]
|Voltage   I(typ)   I(min)   I(max)
-1.8V     -3.876mA   -3.513mA   -4.388mA
-1.305V   -7.581mA   -6.513mA   -8.751mA
-975mV    -26.05mA   -18.22mA   -33.38mA
-755mV    -25.75mA   -20.41mA   -31.24mA
785mV     27.17mA    22.28mA    33.5mA
2.49V     56.65mA    45.81mA    70.33mA
2.71V     54.99mA    33.94mA    70.64mA
2.82V     41.21mA    21.44mA    68.41mA
2.93V     22.67mA    14.25mA    45.37mA
2.985V    17.61mA    12.17mA    30.97mA
3.095V    12.24mA    9.523mA    17.3mA
3.6V      6.353mA    5.495mA    7.528mA
[Pullup]
|Voltage   I(typ)   I(min)   I(max)
-1.8V     2.448mA    2.171mA    2.83mA
-1.24V    6.309mA    5.137mA    7.587mA
-965mV    22.73mA    14.35mA    30.91mA
-745mV    23.89mA    18.57mA    29.07mA
-415mV    16.59mA    12.83mA    20.61mA
795mV     -27.57mA   -21.98mA   -34.72mA
2.5V      -59.1mA    -46.78mA   -74.81mA
2.665V    -59.15mA   -43.78mA   -75.18mA
2.83V     -49.16mA   -26.99mA   -74.23mA
2.94V     -29.32mA   -18.36mA   -56mA
3.105V    -16.86mA   -12.83mA   -23.74mA
3.6V      -10.43mA   -8.489mA   -12.93mA
[GND_clamp]
|Voltage   I(typ)   I(min)   I(max)
-1.8V     -585.7mA   -591.6mA   -585.2mA
-1.097V   -54.7mA    -72.3mA    -45.45mA
-1.06V    -38.22mA   -54.4mA    -30.73mA
-1.023V   -26.05mA   -39.45mA   -21.57mA
-986mV    -18.23mA   -27.86mA   -16.82mA
-949mV    -13.77mA   -19.64mA   -14.3mA
-912mV    -11.21mA   -14.25mA   -12.59mA
-875mV    -9.522mA   -10.86mA   -11.14mA
-727mV    -4.965mA   -4.953mA   -5.98mA
-505mV    -637.4uA   -970.8uA   -651.9uA
-320mV    -95.22uA   -117.2uA   -94.14uA
1.89V     0A         0A         0A
[POWER_clamp]
|Voltage   I(typ)   I(min)   I(max)
-1.789V   650.9mA    666.7mA    643.9mA
-1.086V   73.39mA    99.36mA    59.11mA
-1.049V   53.39mA    77.76mA    41.22mA
-1.012V   37.33mA    58.73mA    28.98mA
-975mV    25.93mA    42.79mA    22.14mA
-938mV    18.88mA    30.44mA    18.64mA
-901mV    14.88mA    21.59mA    16.55mA
-827mV    10.9mA     12.03mA    13.51mA
-716mV    7.349mA    6.765mA    9.446mA
-457mV    1.407mA    1.575mA    1.826mA
-272mV    92.84uA    154.8uA    100.2uA
1.8V      0A         0A         0A
[Ramp]
| variable   typ   min   max
dV/dt_r   0.711/0.140n   0.627/0.169n   0.794/0.116n
dV/dt_f   0.709/0.132n   0.632/0.156n   0.787/0.114n
R_load = 50.000
[Rising Waveform]
R_fixture= 50.000
V_fixture= 0.0
V_fixture_min= 0.0
V_fixture_max= 0.0
|time   V(typ)   V(min)   V(max)
0s        239.2nV    2.446uV    65.57nV
411ps     158.5uV    -99.67uV   13.54mV
470ps     -6.618mV   84.65uV    238.8mV
524ps     32.71mV    -238.7uV   693.4mV
614ps     426.1mV    2.926mV    1.128V
687ps     835.6mV    146.4mV    1.235V
763ps     1.028V     477.2mV    1.281V
890ps     1.135V     866.3mV    1.308V
1.098ns   1.174V     1.009V     1.32V
50ns      1.185V     1.045V     1.324V
[Rising Waveform]
R_fixture= 50.000
V_fixture= 1.800
V_fixture_min= 1.750
V_fixture_max= 1.850
|time   V(typ)   V(min)   V(max)
0s        618mV      696mV      538.5mV
388ps     619.6mV    696.8mV    544.7mV
451ps     616.9mV    697.4mV    915.5mV
490ps     653.4mV    697.5mV    1.293V
527ps     835.1mV    696.2mV    1.616V
577ps     1.146V     709.4mV    1.772V
670ps     1.68V      1.052V     1.833V
755ps     1.771V     1.51V      1.843V
842ps     1.789V     1.69V      1.847V
50ns      1.8V       1.75V      1.85V
[Falling Waveform]
R_fixture= 50.000
V_fixture= 1.800
V_fixture_min= 1.750
V_fixture_max= 1.850
|time   V(typ)   V(min)   V(max)
0s        1.8V       1.75V      1.85V
398ps     1.8V       1.75V      1.839V
495ps     1.787V     1.75V      1.513V
590ps     1.547V     1.742V     817.7mV
686ps     984.7mV    1.577V     609.9mV
742ps     787.6mV    1.391V     576.1mV
858ps     664.4mV    902mV      550mV
999ps     630mV      746mV      541.2mV
2.163ns   618mV      696mV      538.5mV
50ns      618mV      695.9mV    538.5mV
[Falling Waveform]
R_fixture= 50.000
V_fixture= 0.0
V_fixture_min= 0.0
V_fixture_max= 0.0
|time   V(typ)   V(min)   V(max)
0s        1.185V     1.045V     1.324V
399ps     1.185V     1.045V     1.304V
446ps     1.187V     1.045V     1.112V
504ps     1.142V     1.045V     659mV
548ps     975.5mV    1.048V     265.5mV
586ps     746.9mV    1.03V      105.1mV
688ps     131mV      702.3mV    22.87mV
790ps     28.01mV    197.2mV    5.911mV
870ps     10.21mV    54.85mV    1.871mV
50ns      697.5nV    2.817uV    320.4nV
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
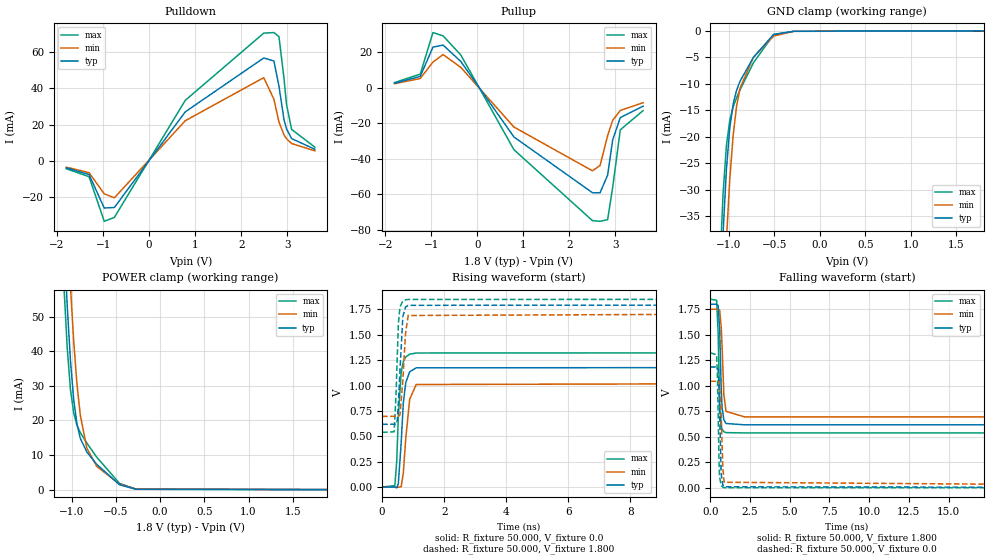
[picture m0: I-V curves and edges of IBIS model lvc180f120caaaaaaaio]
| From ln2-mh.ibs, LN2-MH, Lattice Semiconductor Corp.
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|   Model lvc180f120caaaaaaaio
[Model] lvc180f120caaaaaaaio
Model_type I/O
Polarity   Non-Inverting
Enable   Active-Low
Vinl =  0.630V
Vinh =  1.170V
Vmeas =  0.900V
Cref =  0.0F
Rref =  1.000M
Vref =  0.0V
C_comp   2.000pF   1.500pF   2.500pF
[Temperature Range]   25.000   0.125k   -40.000
[Voltage Range]   1.800V   1.750V   1.850V
[C Comp Corner]
C_comp   2.000pF   1.500pF   2.500pF
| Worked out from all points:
|   slope of the pulldown table from 0 to 0.27 V, typ, clamps not added: 25.7 ohm
|   slope of the pullup table from 0 to 0.27 V, typ, clamps not added: 25.4 ohm
|   GND clamp passes 1 mA (typ) near -0.53 V on its own axis
|   POWER clamp passes 1 mA (typ) near -0.43 V on its own axis
|   rising waveform, R_fixture 50.000, V_fixture 0.0: 20-80 % time 139ps typ, 168ps min, 115ps max; typ from 0 V to 1.19 V
|   rising waveform, R_fixture 50.000, V_fixture 1.800: 20-80 % time 105ps typ, 127ps min, 88.2ps max; typ from 0.618 V to 1.8 V
|   falling waveform, R_fixture 50.000, V_fixture 1.800: 20-80 % time 132ps typ, 156ps min, 114ps max; typ from 1.8 V to 0.618 V
|   falling waveform, R_fixture 50.000, V_fixture 0.0: 20-80 % time 108ps typ, 128ps min, 94.4ps max; typ from 1.19 V to 0 V
[Pulldown]
|Voltage   I(typ)   I(min)   I(max)
-1.8V     -3.87mA    -3.508mA   -4.38mA
-1.305V   -7.572mA   -6.505mA   -8.74mA
-975mV    -26.01mA   -18.2mA    -33.33mA
-755mV    -25.71mA   -20.39mA   -31.19mA
785mV     26.98mA    22.09mA    33.31mA
2.49V     56.68mA    45.83mA    70.36mA
2.71V     55.01mA    33.96mA    70.67mA
2.82V     41.23mA    21.45mA    68.44mA
2.93V     22.68mA    14.25mA    45.39mA
2.985V    17.62mA    12.17mA    30.98mA
3.095V    12.25mA    9.527mA    17.31mA
3.6V      6.355mA    5.497mA    7.531mA
[Pullup]
|Voltage   I(typ)   I(min)   I(max)
-1.8V     2.45mA     2.173mA    2.833mA
-1.24V    6.314mA    5.142mA    7.594mA
-965mV    22.75mA    14.36mA    30.94mA
-745mV    23.92mA    18.58mA    29.1mA
-360mV    14.71mA    11.4mA     18.36mA
795mV     -27.75mA   -22.16mA   -34.9mA
2.5V      -59.06mA   -46.75mA   -74.76mA
2.665V    -59.11mA   -43.75mA   -75.13mA
2.83V     -49.14mA   -26.98mA   -74.18mA
2.94V     -29.31mA   -18.35mA   -55.98mA
3.105V    -16.85mA   -12.82mA   -23.73mA
3.6V      -10.42mA   -8.484mA   -12.92mA
[GND_clamp]
|Voltage   I(typ)   I(min)   I(max)
-1.8V     -585.7mA   -591.6mA   -585.2mA
-1.097V   -54.72mA   -72.32mA   -45.47mA
-1.06V    -38.25mA   -54.42mA   -30.77mA
-1.023V   -26.08mA   -39.47mA   -21.61mA
-986mV    -18.26mA   -27.88mA   -16.87mA
-949mV    -13.8mA    -19.67mA   -14.35mA
-912mV    -11.24mA   -14.28mA   -12.64mA
-875mV    -9.559mA   -10.89mA   -11.19mA
-727mV    -5.003mA   -4.98mA    -6.032mA
-505mV    -676uA     -991.2uA   -711.7uA
-283mV    -81.53uA   -80.08uA   -96.55uA
1.8V      0A         0A         0A
[POWER_clamp]
|Voltage   I(typ)   I(min)   I(max)
-1.789V   650.9mA    666.7mA    643.9mA
-1.086V   73.38mA    99.35mA    59.1mA
-1.049V   53.37mA    77.75mA    41.2mA
-1.012V   37.32mA    58.72mA    28.95mA
-975mV    25.91mA    42.78mA    22.11mA
-938mV    18.86mA    30.43mA    18.61mA
-901mV    14.86mA    21.58mA    16.52mA
-827mV    10.88mA    12.01mA    13.47mA
-716mV    7.324mA    6.749mA    9.413mA
-457mV    1.39mA     1.571mA    1.797mA
-272mV    110.1uA    181.7uA    102.9uA
1.89V     0A         0A         0A
[Ramp]
| variable   typ   min   max
dV/dt_r   0.711/0.140n   0.627/0.169n   0.794/0.116n
dV/dt_f   0.709/0.132n   0.632/0.156n   0.787/0.114n
R_load = 50.000
[Rising Waveform]
R_fixture= 50.000
V_fixture= 0.0
V_fixture_min= 0.0
V_fixture_max= 0.0
|time   V(typ)   V(min)   V(max)
0s        239.2nV    2.446uV    65.57nV
412ps     167.6uV    -99.09uV   15.45mV
472ps     -7.033mV   90.35uV    251.1mV
523ps     30.61mV    -155.6uV   684.3mV
615ps     433mV      3.962mV    1.13V
685ps     827.9mV    139.6mV    1.233V
763ps     1.028V     476.9mV    1.281V
890ps     1.135V     866.1mV    1.308V
1.101ns   1.174V     1.01V      1.32V
50ns      1.185V     1.045V     1.324V
[Rising Waveform]
R_fixture= 50.000
V_fixture= 1.800
V_fixture_min= 1.750
V_fixture_max= 1.850
|time   V(typ)   V(min)   V(max)
0s        618mV      696mV      538.5mV
388ps     619.6mV    696.8mV    544.7mV
451ps     616.8mV    697.4mV    915.5mV
491ps     657.4mV    697.5mV    1.304V
527ps     835.7mV    696.2mV    1.616V
577ps     1.146V     709.6mV    1.772V
670ps     1.68V      1.052V     1.833V
755ps     1.771V     1.51V      1.843V
841ps     1.789V     1.689V     1.847V
50ns      1.8V       1.75V      1.85V
[Falling Waveform]
R_fixture= 50.000
V_fixture= 1.800
V_fixture_min= 1.750
V_fixture_max= 1.850
|time   V(typ)   V(min)   V(max)
0s        1.8V       1.75V      1.85V
398ps     1.8V       1.75V      1.839V
495ps     1.787V     1.75V      1.513V
591ps     1.544V     1.741V     813.2mV
686ps     985.2mV    1.577V     609.9mV
742ps     787.8mV    1.39V      576.1mV
853ps     666.8mV    914.2mV    550.6mV
991ps     631mV      749.7mV    541.4mV
2.152ns   618mV      696mV      538.5mV
50ns      617.9mV    695.9mV    538.5mV
[Falling Waveform]
R_fixture= 50.000
V_fixture= 0.0
V_fixture_min= 0.0
V_fixture_max= 0.0
|time   V(typ)   V(min)   V(max)
0s        1.185V     1.045V     1.324V
399ps     1.185V     1.045V     1.304V
446ps     1.187V     1.045V     1.112V
504ps     1.143V     1.045V     659mV
547ps     981.7mV    1.048V     272.1mV
585ps     753.8mV    1.031V     107.4mV
686ps     137mV      711.5mV    23.42mV
790ps     28.06mV    197.2mV    5.91mV
870ps     10.23mV    54.85mV    1.871mV
50ns      724.4nV    2.817uV    321.9nV
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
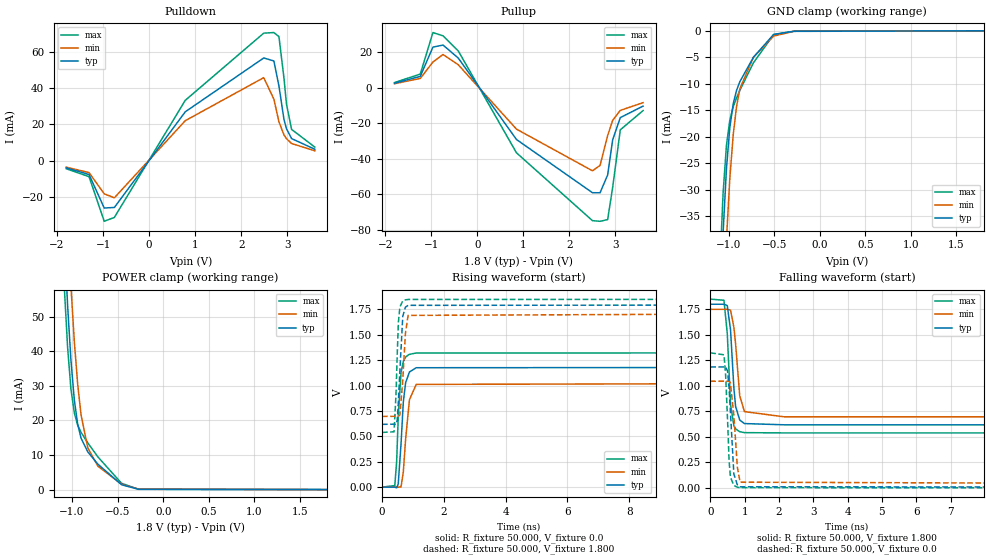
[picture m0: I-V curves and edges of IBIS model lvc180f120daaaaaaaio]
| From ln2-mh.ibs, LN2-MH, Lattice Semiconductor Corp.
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|   Model lvc180f120daaaaaaaio
[Model] lvc180f120daaaaaaaio
Model_type I/O
Polarity   Non-Inverting
Enable   Active-Low
Vinl =  0.630V
Vinh =  1.170V
Vmeas =  0.900V
Cref =  0.0F
Rref =  1.000M
Vref =  0.0V
C_comp   2.000pF   1.500pF   2.500pF
[Temperature Range]   25.000   0.125k   -40.000
[Voltage Range]   1.800V   1.750V   1.850V
[C Comp Corner]
C_comp   2.000pF   1.500pF   2.500pF
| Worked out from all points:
|   slope of the pulldown table from 0 to 0.27 V, typ, clamps not added: 25.7 ohm
|   slope of the pullup table from 0 to 0.27 V, typ, clamps not added: 25.6 ohm
|   GND clamp passes 1 mA (typ) near -0.53 V on its own axis
|   POWER clamp passes 1 mA (typ) near -0.43 V on its own axis
|   rising waveform, R_fixture 50.000, V_fixture 0.0: 20-80 % time 140ps typ, 168ps min, 115ps max; typ from 0 V to 1.19 V
|   rising waveform, R_fixture 50.000, V_fixture 1.800: 20-80 % time 105ps typ, 127ps min, 88.2ps max; typ from 0.618 V to 1.8 V
|   falling waveform, R_fixture 50.000, V_fixture 1.800: 20-80 % time 132ps typ, 156ps min, 114ps max; typ from 1.8 V to 0.618 V
|   falling waveform, R_fixture 50.000, V_fixture 0.0: 20-80 % time 108ps typ, 128ps min, 94.4ps max; typ from 1.19 V to 0 V
[Pulldown]
|Voltage   I(typ)   I(min)   I(max)
-1.8V     -3.87mA    -3.508mA   -4.38mA
-1.305V   -7.572mA   -6.505mA   -8.74mA
-975mV    -26.01mA   -18.2mA    -33.33mA
-755mV    -25.71mA   -20.39mA   -31.19mA
785mV     26.98mA    22.09mA    33.31mA
2.49V     56.65mA    45.81mA    70.33mA
2.71V     54.99mA    33.94mA    70.64mA
2.82V     41.21mA    21.44mA    68.41mA
2.93V     22.67mA    14.25mA    45.37mA
2.985V    17.61mA    12.17mA    30.97mA
3.095V    12.24mA    9.523mA    17.3mA
3.6V      6.353mA    5.495mA    7.528mA
[Pullup]
|Voltage   I(typ)   I(min)   I(max)
-1.8V     2.448mA    2.171mA    2.83mA
-1.24V    6.309mA    5.137mA    7.587mA
-965mV    22.73mA    14.35mA    30.91mA
-745mV    23.89mA    18.57mA    29.07mA
-415mV    16.59mA    12.83mA    20.61mA
850mV     -29.17mA   -23.35mA   -36.65mA
2.5V      -59.06mA   -46.75mA   -74.76mA
2.665V    -59.11mA   -43.75mA   -75.13mA
2.83V     -49.14mA   -26.98mA   -74.18mA
2.94V     -29.31mA   -18.35mA   -55.98mA
3.105V    -16.85mA   -12.82mA   -23.73mA
3.6V      -10.42mA   -8.484mA   -12.92mA
[GND_clamp]
|Voltage   I(typ)   I(min)   I(max)
-1.8V     -585.7mA   -591.6mA   -585.2mA
-1.097V   -54.72mA   -72.32mA   -45.47mA
-1.06V    -38.25mA   -54.42mA   -30.77mA
-1.023V   -26.08mA   -39.47mA   -21.61mA
-986mV    -18.26mA   -27.88mA   -16.87mA
-949mV    -13.8mA    -19.67mA   -14.35mA
-912mV    -11.24mA   -14.28mA   -12.64mA
-875mV    -9.559mA   -10.89mA   -11.19mA
-727mV    -5.003mA   -4.98mA    -6.032mA
-505mV    -676uA     -991.2uA   -711.7uA
-283mV    -81.53uA   -80.08uA   -96.55uA
1.8V      -11.32nA   0A         -15.28uA
[POWER_clamp]
|Voltage   I(typ)   I(min)   I(max)
-1.789V   650.9mA    666.7mA    643.9mA
-1.086V   73.39mA    99.36mA    59.11mA
-1.049V   53.39mA    77.76mA    41.22mA
-1.012V   37.33mA    58.73mA    28.98mA
-975mV    25.93mA    42.79mA    22.14mA
-938mV    18.88mA    30.44mA    18.64mA
-901mV    14.88mA    21.59mA    16.55mA
-827mV    10.9mA     12.03mA    13.51mA
-716mV    7.349mA    6.765mA    9.446mA
-457mV    1.407mA    1.575mA    1.826mA
-272mV    92.84uA    154.8uA    100.2uA
1.8V      0A         0A         15.76uA
[Ramp]
| variable   typ   min   max
dV/dt_r   0.711/0.140n   0.627/0.169n   0.794/0.116n
dV/dt_f   0.709/0.132n   0.632/0.156n   0.787/0.114n
R_load = 50.000
[Rising Waveform]
R_fixture= 50.000
V_fixture= 0.0
V_fixture_min= 0.0
V_fixture_max= 0.0
|time   V(typ)   V(min)   V(max)
0s        239.2nV    2.446uV    65.57nV
412ps     165.9uV    -99.06uV   15.45mV
472ps     -7.015mV   90.37uV    251.1mV
523ps     30.37mV    -149.4uV   684.3mV
614ps     425.7mV    2.814mV    1.128V
687ps     835.4mV    146.2mV    1.235V
762ps     1.027V     472.2mV    1.281V
886ps     1.133V     859.8mV    1.307V
1.106ns   1.175V     1.011V     1.32V
50ns      1.185V     1.045V     1.324V
[Rising Waveform]
R_fixture= 50.000
V_fixture= 1.800
V_fixture_min= 1.750
V_fixture_max= 1.850
|time   V(typ)   V(min)   V(max)
0s        618mV      696mV      538.5mV
388ps     619.6mV    696.8mV    544.7mV
451ps     616.8mV    697.4mV    915.5mV
491ps     657.3mV    697.5mV    1.304V
528ps     840.8mV    696.1mV    1.621V
577ps     1.146V     709.4mV    1.772V
670ps     1.68V      1.052V     1.833V
755ps     1.771V     1.51V      1.843V
842ps     1.789V     1.69V      1.847V
50ns      1.8V       1.75V      1.85V
[Falling Waveform]
R_fixture= 50.000
V_fixture= 1.800
V_fixture_min= 1.750
V_fixture_max= 1.850
|time   V(typ)   V(min)   V(max)
0s        1.8V       1.75V      1.85V
398ps     1.8V       1.75V      1.839V
495ps     1.787V     1.75V      1.513V
590ps     1.548V     1.742V     817.7mV
688ps     975.1mV    1.572V     608.3mV
738ps     797mV      1.408V     577.8mV
858ps     664.5mV    901.9mV    550mV
996ps     630.3mV    747.3mV    541.3mV
2.162ns   618mV      696mV      538.5mV
50ns      618mV      695.9mV    538.5mV
[Falling Waveform]
R_fixture= 50.000
V_fixture= 0.0
V_fixture_min= 0.0
V_fixture_max= 0.0
|time   V(typ)   V(min)   V(max)
0s        1.185V     1.045V     1.324V
399ps     1.185V     1.045V     1.304V
446ps     1.187V     1.045V     1.112V
504ps     1.143V     1.045V     659mV
547ps     981.7mV    1.048V     272.1mV
585ps     753.8mV    1.031V     107.4mV
686ps     137mV      711.8mV    23.42mV
789ps     28.41mV    200.9mV    5.996mV
869ps     10.37mV    55.62mV    1.897mV
50ns      724.4nV    2.8uV      322nV
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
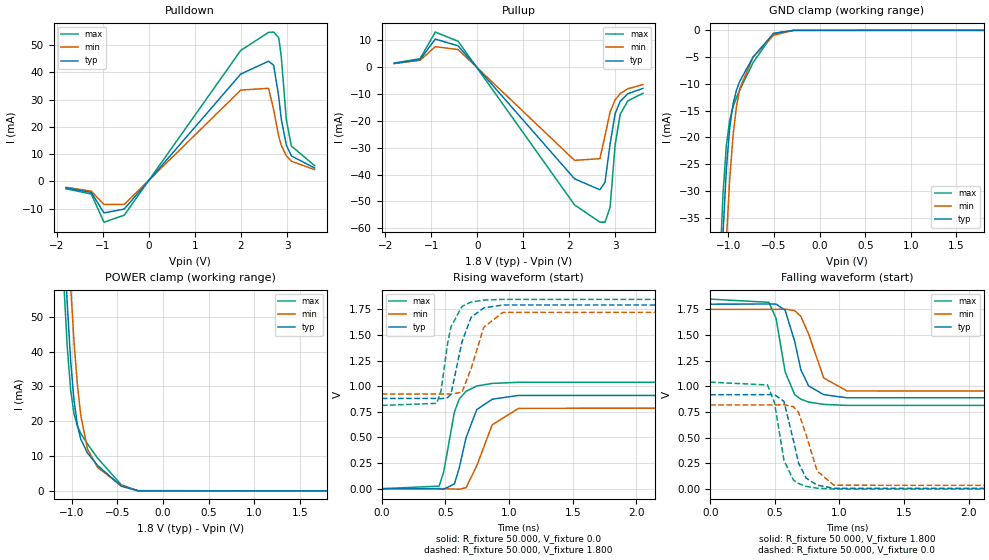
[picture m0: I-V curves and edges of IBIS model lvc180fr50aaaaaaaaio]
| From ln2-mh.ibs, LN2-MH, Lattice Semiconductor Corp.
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|   Model lvc180fr50aaaaaaaaio
[Model] lvc180fr50aaaaaaaaio
Model_type I/O
Polarity   Non-Inverting
Enable   Active-Low
Vinl =  0.630V
Vinh =  1.170V
Vmeas =  0.900V
Cref =  0.0F
Rref =  1.000M
Vref =  0.0V
C_comp   2.000pF   1.500pF   2.500pF
[Temperature Range]   25.000   0.125k   -40.000
[Voltage Range]   1.800V   1.750V   1.850V
[C Comp Corner]
C_comp   2.000pF   1.500pF   2.500pF
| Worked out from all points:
|   slope of the pulldown table from 0 to 0.27 V, typ, clamps not added: 49.6 ohm
|   slope of the pullup table from 0 to 0.27 V, typ, clamps not added: 49.6 ohm
|   GND clamp passes 1 mA (typ) near -0.54 V on its own axis
|   POWER clamp passes 1 mA (typ) near -0.43 V on its own axis
|   rising waveform, R_fixture 50.000, V_fixture 0.0: 20-80 % time 123ps typ, 156ps min, 99.9ps max; typ from 0 V to 0.919 V
|   rising waveform, R_fixture 50.000, V_fixture 1.800: 20-80 % time 102ps typ, 121ps min, 85.3ps max; typ from 0.881 V to 1.8 V
|   falling waveform, R_fixture 50.000, V_fixture 1.800: 20-80 % time 108ps typ, 133ps min, 93.4ps max; typ from 1.8 V to 0.881 V
|   falling waveform, R_fixture 50.000, V_fixture 0.0: 20-80 % time 100ps typ, 118ps min, 88.8ps max; typ from 0.919 V to 0 V
[Pulldown]
|Voltage   I(typ)   I(min)   I(max)
-1.8V     -2.363mA   -2.137mA   -2.722mA
-1.25V    -4.032mA   -3.596mA   -4.637mA
-975mV    -11.57mA   -8.474mA   -14.98mA
-535mV    -10.16mA   -8.453mA   -12.41mA
1.995V    39.39mA    33.51mA    48.07mA
2.6V      44.12mA    34.16mA    54.7mA
2.71V     42.6mA     26.25mA    54.8mA
2.82V     31.06mA    16.51mA    52.73mA
2.875V    22.88mA    13.26mA    45.79mA
2.985V    13.32mA    9.433mA    22.58mA
3.095V    9.348mA    7.405mA    12.96mA
3.6V      4.909mA    4.29mA     5.793mA
[Pullup]
|Voltage   I(typ)   I(min)   I(max)
-1.8V     1.312mA    1.24mA     1.445mA
-1.24V    2.721mA    2.444mA    3.082mA
-910mV    10.35mA    7.537mA    12.94mA
-415mV    7.828mA    6.445mA    9.541mA
2.115V    -41.6mA    -34.74mA   -51.29mA
2.665V    -45.66mA   -34.1mA    -57.69mA
2.775V    -42.89mA   -25.6mA    -57.71mA
2.885V    -28.74mA   -16.79mA   -52.24mA
2.995V    -17.38mA   -12.23mA   -28.99mA
3.105V    -12.79mA   -9.915mA   -17.63mA
3.27V     -9.975mA   -8.121mA   -12.61mA
3.6V      -7.975mA   -6.563mA   -9.828mA
[GND_clamp]
|Voltage   I(typ)   I(min)   I(max)
-1.8V     -585.7mA   -591.6mA   -585.2mA
-1.097V   -54.7mA    -72.3mA    -45.44mA
-1.06V    -38.22mA   -54.4mA    -30.73mA
-1.023V   -26.04mA   -39.44mA   -21.56mA
-986mV    -18.22mA   -27.85mA   -16.81mA
-949mV    -13.75mA   -19.63mA   -14.29mA
-912mV    -11.19mA   -14.24mA   -12.58mA
-875mV    -9.506mA   -10.84mA   -11.12mA
-727mV    -4.941mA   -4.928mA   -5.958mA
-505mV    -576.1uA   -916.7uA   -589.6uA
-283mV    -824.2nA   -10.84uA   -168.9nA
1.8V      0A         0A         0A
[POWER_clamp]
|Voltage   I(typ)   I(min)   I(max)
-1.789V   650.9mA    666.7mA    643.9mA
-1.086V   73.37mA    99.35mA    59.09mA
-1.049V   53.37mA    77.75mA    41.19mA
-1.012V   37.31mA    58.71mA    28.94mA
-975mV    25.9mA     42.77mA    22.1mA
-938mV    18.85mA    30.42mA    18.6mA
-901mV    14.84mA    21.56mA    16.51mA
-827mV    10.86mA    11.99mA    13.46mA
-716mV    7.305mA    6.728mA    9.397mA
-457mV    1.344mA    1.526mA    1.755mA
-272mV    20.87uA    98.79uA    12.36uA
1.8V      0A         0A         0A
[Ramp]
| variable   typ   min   max
dV/dt_r   0.551/0.123n   0.492/0.156n   0.624/0.100n
dV/dt_f   0.552/0.108n   0.496/0.134n   0.623/94.175p
R_load = 50.000
[Rising Waveform]
R_fixture= 50.000
V_fixture= 0.0
V_fixture_min= 0.0
V_fixture_max= 0.0
|time   V(typ)   V(min)   V(max)
0s        367.3nV    3.507uV    105.1nV
450ps     -1.096mV   -4.826uV   25.07mV
486ps     -4.59mV    94.5uV     162.3mV
570ps     47.22mV    -3.533mV   747.3mV
608ps     201.6mV    -4.575mV   873.8mV
662ps     499.1mV    9.847mV    950.6mV
746ps     771.8mV    225.1mV    1.002V
867ps     872.8mV    623.1mV    1.027V
1.075ns   909.8mV    784.3mV    1.038V
50ns      918.9mV    819.7mV    1.041V
[Rising Waveform]
R_fixture= 50.000
V_fixture= 1.800
V_fixture_min= 1.750
V_fixture_max= 1.850
|time   V(typ)   V(min)   V(max)
0s        880.5mV    923.9mV    812.4mV
431ps     880.8mV    924.1mV    832.7mV
465ps     878.2mV    924.2mV    953.1mV
516ps     887.8mV    924.2mV    1.413V
543ps     922.9mV    922.8mV    1.578V
630ps     1.433V     941.8mV    1.779V
701ps     1.671V     1.17V      1.821V
801ps     1.764V     1.575V     1.84V
951ps     1.792V     1.72V      1.847V
50ns      1.8V       1.75V      1.85V
[Falling Waveform]
R_fixture= 50.000
V_fixture= 1.800
V_fixture_min= 1.750
V_fixture_max= 1.850
|time   V(typ)   V(min)   V(max)
0s        1.8V       1.75V      1.85V
455ps     1.802V     1.75V      1.818V
510ps     1.801V     1.75V      1.662V
580ps     1.742V     1.752V     1.143V
654ps     1.439V     1.738V     920.2mV
702ps     1.162V     1.682V     875.4mV
762ps     1.005V     1.509V     847.8mV
879ps     919.9mV    1.082V     825.1mV
1.059ns   889.3mV    956mV      815mV
50ns      880.5mV    923.9mV    812.4mV
[Falling Waveform]
R_fixture= 50.000
V_fixture= 0.0
V_fixture_min= 0.0
V_fixture_max= 0.0
|time   V(typ)   V(min)   V(max)
0s        918.9mV    819.7mV    1.041V
444ps     919.9mV    819.7mV    1.014V
498ps     920.2mV    819.7mV    840.1mV
571ps     854.1mV    821.7mV    281.2mV
644ps     475.4mV    802.4mV    89.68mV
684ps     253.2mV    747.2mV    54.97mV
743ps     107.7mV    527.6mV    27.43mV
828ps     39.52mV    176mV      9.156mV
958ps     8.284mV    38.14mV    1.657mV
50ns      1.179uV    4.045uV    562.8nV
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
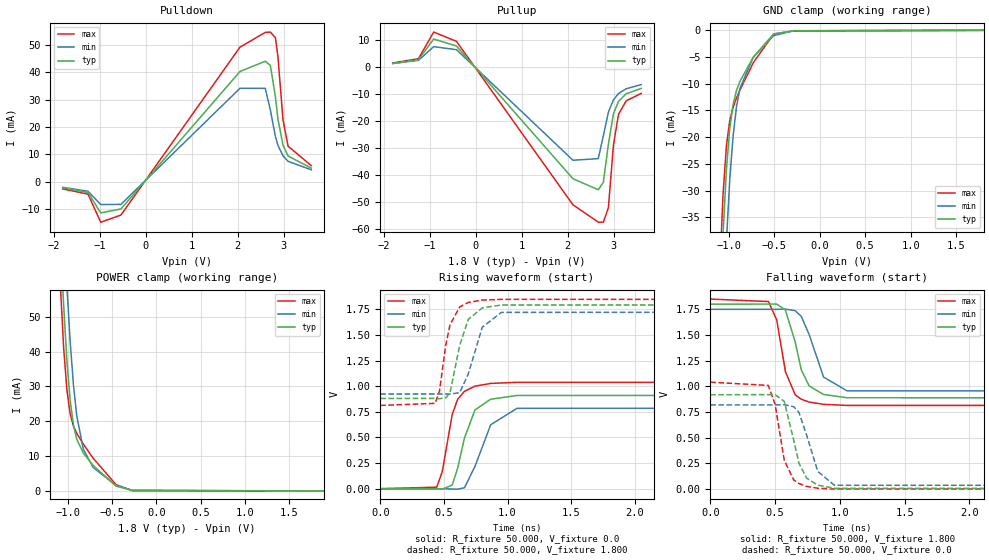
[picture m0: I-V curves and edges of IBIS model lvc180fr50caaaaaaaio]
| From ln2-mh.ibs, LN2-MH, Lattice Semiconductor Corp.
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|   Model lvc180fr50caaaaaaaio
[Model] lvc180fr50caaaaaaaio
Model_type I/O
Polarity   Non-Inverting
Enable   Active-Low
Vinl =  0.630V
Vinh =  1.170V
Vmeas =  0.900V
Cref =  0.0F
Rref =  1.000M
Vref =  0.0V
C_comp   2.000pF   1.500pF   2.500pF
[Temperature Range]   25.000   0.125k   -40.000
[Voltage Range]   1.800V   1.750V   1.850V
[C Comp Corner]
C_comp   2.000pF   1.500pF   2.500pF
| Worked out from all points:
|   slope of the pulldown table from 0 to 0.27 V, typ, clamps not added: 50.2 ohm
|   slope of the pullup table from 0 to 0.27 V, typ, clamps not added: 49.6 ohm
|   GND clamp passes 1 mA (typ) near -0.53 V on its own axis
|   POWER clamp passes 1 mA (typ) near -0.43 V on its own axis
|   rising waveform, R_fixture 50.000, V_fixture 0.0: 20-80 % time 123ps typ, 156ps min, 99.9ps max; typ from 0 V to 0.919 V
|   rising waveform, R_fixture 50.000, V_fixture 1.800: 20-80 % time 101ps typ, 121ps min, 85.3ps max; typ from 0.881 V to 1.8 V
|   falling waveform, R_fixture 50.000, V_fixture 1.800: 20-80 % time 108ps typ, 133ps min, 93.2ps max; typ from 1.8 V to 0.881 V
|   falling waveform, R_fixture 50.000, V_fixture 0.0: 20-80 % time 100ps typ, 118ps min, 88.9ps max; typ from 0.919 V to 0 V
[Pulldown]
|Voltage   I(typ)   I(min)   I(max)
-1.8V     -2.355mA   -2.13mA    -2.713mA
-1.25V    -4.018mA   -3.583mA   -4.621mA
-975mV    -11.52mA   -8.44mA    -14.92mA
-535mV    -10.07mA   -8.383mA   -12.3mA
2.05V     40.33mA    34.18mA    49.26mA
2.6V      44.1mA     34.15mA    54.68mA
2.71V     42.59mA    26.24mA    54.79mA
2.82V     31.06mA    16.5mA     52.72mA
2.875V    22.87mA    13.25mA    45.78mA
2.985V    13.32mA    9.43mA     22.58mA
3.095V    9.346mA    7.403mA    12.96mA
3.6V      4.908mA    4.289mA    5.792mA
[Pullup]
|Voltage   I(typ)   I(min)   I(max)
-1.8V     1.311mA    1.238mA    1.444mA
-1.24V    2.718mA    2.441mA    3.08mA
-910mV    10.34mA    7.524mA    12.93mA
-415mV    7.772mA    6.392mA    9.489mA
2.115V    -41.51mA   -34.65mA   -51.2mA
2.665V    -45.61mA   -34.06mA   -57.62mA
2.775V    -42.85mA   -25.57mA   -57.65mA
2.885V    -28.71mA   -16.77mA   -52.2mA
2.995V    -17.37mA   -12.22mA   -28.96mA
3.105V    -12.77mA   -9.905mA   -17.61mA
3.27V     -9.966mA   -8.112mA   -12.6mA
3.6V      -7.967mA   -6.556mA   -9.819mA
[GND_clamp]
|Voltage   I(typ)   I(min)   I(max)
-1.8V     -585.7mA   -591.6mA   -585.2mA
-1.097V   -54.72mA   -72.32mA   -45.47mA
-1.06V    -38.25mA   -54.42mA   -30.77mA
-1.023V   -26.08mA   -39.47mA   -21.61mA
-986mV    -18.26mA   -27.88mA   -16.87mA
-949mV    -13.8mA    -19.67mA   -14.35mA
-912mV    -11.24mA   -14.28mA   -12.64mA
-875mV    -9.559mA   -10.89mA   -11.19mA
-727mV    -5.003mA   -4.98mA    -6.032mA
-505mV    -676uA     -991.2uA   -711.7uA
-283mV    -81.53uA   -80.08uA   -96.55uA
1.8V      0A         0A         0A
[POWER_clamp]
|Voltage   I(typ)   I(min)   I(max)
-1.789V   650.9mA    666.7mA    643.9mA
-1.086V   73.38mA    99.35mA    59.1mA
-1.049V   53.37mA    77.75mA    41.2mA
-1.012V   37.32mA    58.72mA    28.95mA
-975mV    25.91mA    42.78mA    22.11mA
-938mV    18.86mA    30.43mA    18.61mA
-901mV    14.86mA    21.58mA    16.52mA
-827mV    10.88mA    12.01mA    13.47mA
-716mV    7.324mA    6.749mA    9.413mA
-457mV    1.39mA     1.571mA    1.797mA
-272mV    110.1uA    181.7uA    102.9uA
1.89V     0A         0A         0A
[Ramp]
| variable   typ   min   max
dV/dt_r   0.551/0.123n   0.492/0.156n   0.624/0.100n
dV/dt_f   0.552/0.108n   0.496/0.134n   0.623/94.059p
R_load = 50.000
[Rising Waveform]
R_fixture= 50.000
V_fixture= 0.0
V_fixture_min= 0.0
V_fixture_max= 0.0
|time   V(typ)   V(min)   V(max)
0s        367.3nV    3.507uV    105.1nV
443ps     -488.2uV   -26.76uV   14.8mV
486ps     -4.544mV   94.82uV    161.8mV
565ps     35.58mV    -3.136mV   723.5mV
608ps     201.5mV    -4.576mV   873.4mV
661ps     493.9mV    9.005mV    949.5mV
744ps     768.3mV    217.6mV    1.001V
867ps     872.8mV    623.3mV    1.027V
1.074ns   909.7mV    784.1mV    1.038V
50ns      918.9mV    819.7mV    1.041V
[Rising Waveform]
R_fixture= 50.000
V_fixture= 1.800
V_fixture_min= 1.750
V_fixture_max= 1.850
|time   V(typ)   V(min)   V(max)
0s        880.5mV    923.9mV    812.4mV
431ps     880.8mV    924.1mV    832.7mV
465ps     878.1mV    924.2mV    953.1mV
515ps     887.4mV    924.2mV    1.405V
548ps     936.2mV    922.4mV    1.601V
624ps     1.399V     936.9mV    1.773V
691ps     1.651V     1.119V     1.817V
801ps     1.764V     1.575V     1.84V
951ps     1.792V     1.72V      1.847V
50ns      1.8V       1.75V      1.85V
[Falling Waveform]
R_fixture= 50.000
V_fixture= 1.800
V_fixture_min= 1.750
V_fixture_max= 1.850
|time   V(typ)   V(min)   V(max)
0s        1.8V       1.75V      1.85V
449ps     1.801V     1.75V      1.826V
513ps     1.801V     1.75V      1.646V
580ps     1.742V     1.752V     1.143V
655ps     1.433V     1.737V     918.7mV
702ps     1.162V     1.682V     875.3mV
763ps     1.004V     1.504V     847.5mV
874ps     921.7mV    1.091V     825.6mV
1.055ns   889.6mV    957mV      815.1mV
50ns      880.5mV    923.9mV    812.4mV
[Falling Waveform]
R_fixture= 50.000
V_fixture= 0.0
V_fixture_min= 0.0
V_fixture_max= 0.0
|time   V(typ)   V(min)   V(max)
0s        918.9mV    819.7mV    1.041V
447ps     920.1mV    819.7mV    1.01V
500ps     919.9mV    819.7mV    827.3mV
571ps     854.1mV    821.7mV    281.4mV
644ps     475.4mV    802.4mV    89.74mV
684ps     253.2mV    747.2mV    54.99mV
743ps     107.7mV    527.6mV    27.43mV
829ps     39.06mV    173.7mV    9.04mV
958ps     8.275mV    38.14mV    1.657mV
50ns      1.171uV    4.045uV    563.3nV
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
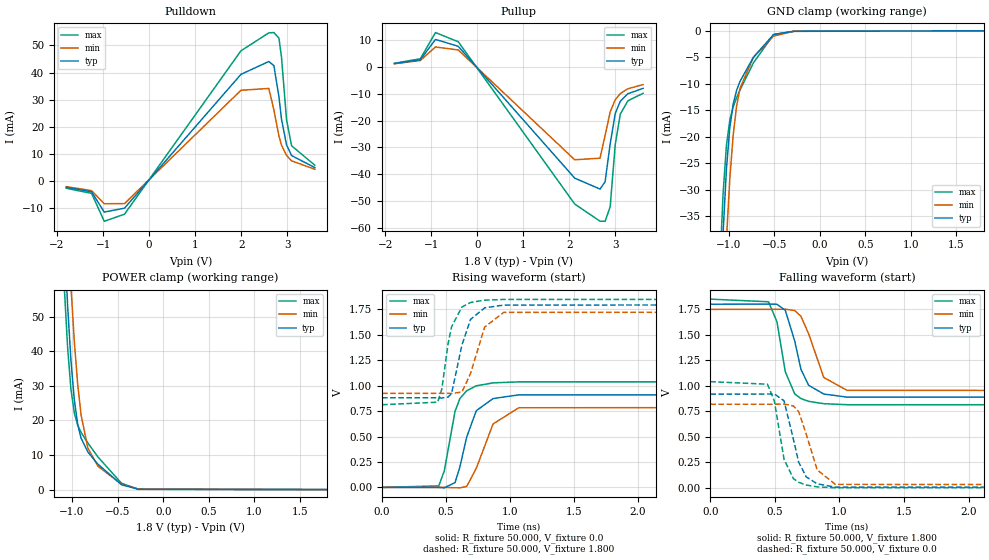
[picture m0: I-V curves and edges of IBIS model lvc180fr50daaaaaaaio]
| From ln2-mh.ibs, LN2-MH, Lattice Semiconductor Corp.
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|   Model lvc180fr50daaaaaaaio
[Model] lvc180fr50daaaaaaaio
Model_type I/O
Polarity   Non-Inverting
Enable   Active-Low
Vinl =  0.630V
Vinh =  1.170V
Vmeas =  0.900V
Cref =  0.0F
Rref =  1.000M
Vref =  0.0V
C_comp   2.000pF   1.500pF   2.500pF
[Temperature Range]   25.000   0.125k   -40.000
[Voltage Range]   1.800V   1.750V   1.850V
[C Comp Corner]
C_comp   2.000pF   1.500pF   2.500pF
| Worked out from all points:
|   slope of the pulldown table from 0 to 0.27 V, typ, clamps not added: 50.2 ohm
|   slope of the pullup table from 0 to 0.27 V, typ, clamps not added: 50.2 ohm
|   GND clamp passes 1 mA (typ) near -0.53 V on its own axis
|   POWER clamp passes 1 mA (typ) near -0.43 V on its own axis
|   rising waveform, R_fixture 50.000, V_fixture 0.0: 20-80 % time 123ps typ, 156ps min, 100ps max; typ from 0 V to 0.919 V
|   rising waveform, R_fixture 50.000, V_fixture 1.800: 20-80 % time 101ps typ, 121ps min, 85.3ps max; typ from 0.881 V to 1.8 V
|   falling waveform, R_fixture 50.000, V_fixture 1.800: 20-80 % time 108ps typ, 133ps min, 93.3ps max; typ from 1.8 V to 0.881 V
|   falling waveform, R_fixture 50.000, V_fixture 0.0: 20-80 % time 100ps typ, 118ps min, 88.8ps max; typ from 0.919 V to 0 V
[Pulldown]
|Voltage   I(typ)   I(min)   I(max)
-1.8V     -2.355mA   -2.13mA    -2.713mA
-1.25V    -4.018mA   -3.583mA   -4.621mA
-975mV    -11.52mA   -8.44mA    -14.92mA
-535mV    -10.07mA   -8.383mA   -12.3mA
1.995V    39.34mA    33.46mA    48.03mA
2.6V      44.08mA    34.13mA    54.65mA
2.71V     42.56mA    26.23mA    54.76mA
2.82V     31.04mA    16.49mA    52.69mA
2.875V    22.86mA    13.25mA    45.76mA
2.985V    13.31mA    9.425mA    22.57mA
3.095V    9.341mA    7.399mA    12.95mA
3.6V      4.905mA    4.287mA    5.788mA
[Pullup]
|Voltage   I(typ)   I(min)   I(max)
-1.8V     1.308mA    1.236mA    1.44mA
-1.24V    2.712mA    2.436mA    3.073mA
-910mV    10.32mA    7.509mA    12.89mA
-415mV    7.759mA    6.393mA    9.463mA
2.115V    -41.51mA   -34.65mA   -51.2mA
2.665V    -45.61mA   -34.06mA   -57.62mA
2.775V    -42.85mA   -25.57mA   -57.65mA
2.885V    -28.71mA   -16.77mA   -52.2mA
2.995V    -17.37mA   -12.22mA   -28.96mA
3.105V    -12.77mA   -9.905mA   -17.61mA
3.27V     -9.966mA   -8.112mA   -12.6mA
3.6V      -7.967mA   -6.556mA   -9.819mA
[GND_clamp]
|Voltage   I(typ)   I(min)   I(max)
-1.8V     -585.7mA   -591.6mA   -585.2mA
-1.097V   -54.72mA   -72.32mA   -45.47mA
-1.06V    -38.25mA   -54.42mA   -30.77mA
-1.023V   -26.08mA   -39.47mA   -21.61mA
-986mV    -18.26mA   -27.88mA   -16.87mA
-949mV    -13.8mA    -19.67mA   -14.35mA
-912mV    -11.24mA   -14.28mA   -12.64mA
-875mV    -9.559mA   -10.89mA   -11.19mA
-727mV    -5.003mA   -4.98mA    -6.032mA
-505mV    -676uA     -991.2uA   -711.7uA
-283mV    -81.53uA   -80.08uA   -96.55uA
1.8V      -11.32nA   0A         -15.28uA
[POWER_clamp]
|Voltage   I(typ)   I(min)   I(max)
-1.789V   650.9mA    666.7mA    643.9mA
-1.086V   73.39mA    99.36mA    59.11mA
-1.049V   53.39mA    77.76mA    41.22mA
-1.012V   37.33mA    58.73mA    28.98mA
-975mV    25.93mA    42.79mA    22.14mA
-938mV    18.88mA    30.44mA    18.64mA
-901mV    14.88mA    21.59mA    16.55mA
-827mV    10.9mA     12.03mA    13.51mA
-716mV    7.349mA    6.765mA    9.446mA
-457mV    1.407mA    1.575mA    1.826mA
-272mV    92.84uA    154.8uA    100.2uA
1.8V      0A         0A         15.76uA
[Ramp]
| variable   typ   min   max
dV/dt_r   0.551/0.123n   0.492/0.156n   0.624/0.100n
dV/dt_f   0.552/0.108n   0.496/0.134n   0.623/94.176p
R_load = 50.000
[Rising Waveform]
R_fixture= 50.000
V_fixture= 0.0
V_fixture_min= 0.0
V_fixture_max= 0.0
|time   V(typ)   V(min)   V(max)
0s        367.3nV    3.507uV    105.1nV
443ps     -494.8uV   -26.52uV   14.8mV
486ps     -4.59mV    95.07uV    161.8mV
570ps     47.22mV    -3.547mV   746.7mV
608ps     201.6mV    -4.575mV   873.4mV
661ps     494mV      9.1mV      949.5mV
736ps     753.6mV    187.3mV    998.3mV
867ps     872.8mV    623.4mV    1.027V
1.068ns   909.3mV    782.6mV    1.037V
50ns      918.9mV    819.7mV    1.041V
[Rising Waveform]
R_fixture= 50.000
V_fixture= 1.800
V_fixture_min= 1.750
V_fixture_max= 1.850
|time   V(typ)   V(min)   V(max)
0s        880.5mV    923.9mV    812.4mV
434ps     880.7mV    924.1mV    837.3mV
467ps     878mV      924.2mV    967.4mV
516ps     887.8mV    924.2mV    1.414V
543ps     922.9mV    922.8mV    1.578V
624ps     1.399V     936.9mV    1.773V
691ps     1.651V     1.119V     1.817V
801ps     1.764V     1.575V     1.84V
951ps     1.792V     1.72V      1.847V
50ns      1.8V       1.75V      1.85V
[Falling Waveform]
R_fixture= 50.000
V_fixture= 1.800
V_fixture_min= 1.750
V_fixture_max= 1.850
|time   V(typ)   V(min)   V(max)
0s        1.8V       1.75V      1.85V
451ps     1.801V     1.75V      1.824V
516ps     1.8V       1.75V      1.629V
581ps     1.74V      1.752V     1.138V
654ps     1.439V     1.738V     920.1mV
702ps     1.162V     1.682V     875.5mV
762ps     1.005V     1.509V     847.8mV
879ps     919.9mV    1.082V     825.1mV
1.059ns   889.3mV    956mV      815mV
50ns      880.5mV    923.9mV    812.4mV
[Falling Waveform]
R_fixture= 50.000
V_fixture= 0.0
V_fixture_min= 0.0
V_fixture_max= 0.0
|time   V(typ)   V(min)   V(max)
0s        918.9mV    819.7mV    1.041V
443ps     919.9mV    819.7mV    1.016V
496ps     920.5mV    819.7mV    852.8mV
571ps     854.1mV    821.7mV    280.6mV
644ps     475.4mV    802.4mV    89.72mV
684ps     253.2mV    747.2mV    55.02mV
743ps     107.7mV    527.6mV    27.46mV
828ps     39.52mV    176mV      9.174mV
969ps     7.23mV     33.76mV    1.44mV
50ns      1.174uV    4.045uV    562.3nV
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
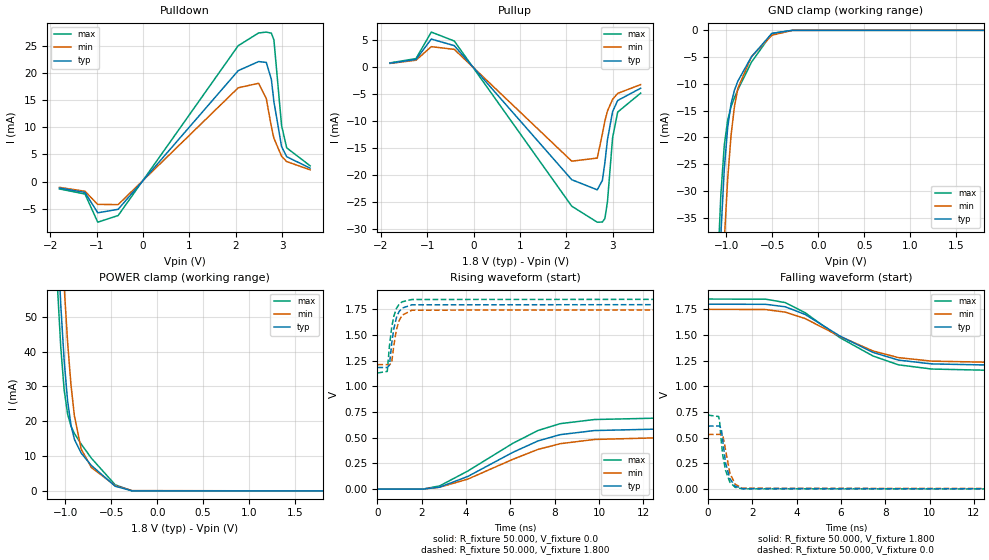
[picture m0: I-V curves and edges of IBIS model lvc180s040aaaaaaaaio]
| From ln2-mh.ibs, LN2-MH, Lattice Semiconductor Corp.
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|   Model lvc180s040aaaaaaaaio
[Model] lvc180s040aaaaaaaaio
Model_type I/O
Polarity   Non-Inverting
Enable   Active-Low
Vinl =  0.630V
Vinh =  1.170V
Vmeas =  0.900V
Cref =  0.0F
Rref =  1.000M
Vref =  0.0V
C_comp   2.000pF   1.500pF   2.500pF
[Temperature Range]   25.000   0.125k   -40.000
[Voltage Range]   1.800V   1.750V   1.850V
[C Comp Corner]
C_comp   2.000pF   1.500pF   2.500pF
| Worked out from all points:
|   slope of the pulldown table from 0 to 0.27 V, typ, clamps not added: 98.3 ohm
|   slope of the pullup table from 0 to 0.27 V, typ, clamps not added: 98.7 ohm
|   GND clamp passes 1 mA (typ) near -0.54 V on its own axis
|   POWER clamp passes 1 mA (typ) near -0.43 V on its own axis
|   rising waveform, R_fixture 50.000, V_fixture 0.0: 20-80 % time 3.46ns typ, 3.7ns min, 3.46ns max; typ from 0 V to 0.614 V
|   rising waveform, R_fixture 50.000, V_fixture 1.800: 20-80 % time 275ps typ, 283ps min, 269ps max; typ from 1.18 V to 1.8 V
|   falling waveform, R_fixture 50.000, V_fixture 1.800: 20-80 % time 3.15ns typ, 3.25ns min, 3.21ns max; typ from 1.8 V to 1.18 V
|   falling waveform, R_fixture 50.000, V_fixture 0.0: 20-80 % time 293ps typ, 301ps min, 287ps max; typ from 0.614 V to 0 V
[Pulldown]
|Voltage   I(typ)   I(min)   I(max)
-1.8V     -1.177mA   -1.065mA   -1.357mA
-1.25V    -1.996mA   -1.784mA   -2.29mA
-975mV    -5.74mA    -4.198mA   -7.469mA
-535mV    -5.098mA   -4.235mA   -6.24mA
2.05V     20.39mA    17.24mA    24.98mA
2.49V     22.07mA    18.07mA    27.33mA
2.655V    21.92mA    15.28mA    27.49mA
2.765V    18.79mA    10.1mA     27.29mA
2.82V     14.69mA    7.966mA    26.04mA
2.985V    6.431mA    4.647mA    10.31mA
3.095V    4.574mA    3.677mA    6.203mA
3.6V      2.462mA    2.162mA    2.901mA
[Pullup]
|Voltage   I(typ)   I(min)   I(max)
-1.8V     652.6uA    617.7uA    718uA
-1.24V    1.342mA    1.21mA     1.513mA
-910mV    5.133mA    3.729mA    6.429mA
-415mV    3.914mA    3.222mA    4.773mA
2.115V    -20.95mA   -17.51mA   -25.86mA
2.665V    -22.83mA   -16.94mA   -28.83mA
2.775V    -21.08mA   -12.45mA   -28.8mA
2.83V     -17.74mA   -10.06mA   -28.14mA
2.885V    -13.52mA   -8.198mA   -25.02mA
2.995V    -8.328mA   -6.044mA   -13.18mA
3.105V    -6.254mA   -4.938mA   -8.404mA
3.6V      -3.983mA   -3.31mA    -4.885mA
[GND_clamp]
|Voltage   I(typ)   I(min)   I(max)
-1.8V     -585.7mA   -591.6mA   -585.2mA
-1.097V   -54.7mA    -72.3mA    -45.44mA
-1.06V    -38.22mA   -54.4mA    -30.73mA
-1.023V   -26.04mA   -39.44mA   -21.56mA
-986mV    -18.22mA   -27.85mA   -16.81mA
-949mV    -13.75mA   -19.63mA   -14.29mA
-912mV    -11.19mA   -14.24mA   -12.58mA
-875mV    -9.506mA   -10.84mA   -11.12mA
-727mV    -4.941mA   -4.928mA   -5.958mA
-505mV    -576.1uA   -916.7uA   -589.6uA
-283mV    -824.2nA   -10.84uA   -168.9nA
1.8V      0A         0A         0A
[POWER_clamp]
|Voltage   I(typ)   I(min)   I(max)
-1.789V   650.9mA    666.7mA    643.9mA
-1.086V   73.37mA    99.35mA    59.09mA
-1.049V   53.37mA    77.75mA    41.19mA
-1.012V   37.31mA    58.71mA    28.94mA
-975mV    25.9mA     42.77mA    22.1mA
-938mV    18.85mA    30.42mA    18.6mA
-901mV    14.84mA    21.56mA    16.51mA
-827mV    10.86mA    11.99mA    13.46mA
-716mV    7.305mA    6.728mA    9.397mA
-457mV    1.344mA    1.526mA    1.755mA
-272mV    20.87uA    98.79uA    12.36uA
1.8V      0A         0A         0A
[Ramp]
| variable   typ   min   max
dV/dt_r   0.368/3.475n   0.319/3.715n   0.432/3.460n
dV/dt_f   0.369/3.179n   0.323/3.255n   0.432/3.224n
R_load = 50.000
[Rising Waveform]
R_fixture= 50.000
V_fixture= 0.0
V_fixture_min= 0.0
V_fixture_max= 0.0
|time   V(typ)   V(min)   V(max)
0s        816.5nV    7.287uV    250.2nV
2.059ns   557.2uV    1.733mV    1.466mV
2.803ns   19.36mV    18.81mV    31.54mV
4.073ns   123.5mV    97.42mV    176mV
6.103ns   357.9mV    290.1mV    445.6mV
7.249ns   470mV      387.4mV    571.6mV
8.243ns   530.4mV    442.4mV    637.4mV
9.784ns   570.4mV    483.6mV    677.7mV
18.16ns   612.3mV    531.2mV    717.8mV
50ns      613.9mV    532.4mV    720.7mV
[Rising Waveform]
R_fixture= 50.000
V_fixture= 1.800
V_fixture_min= 1.750
V_fixture_max= 1.850
|time   V(typ)   V(min)   V(max)
0s        1.184V     1.212V     1.13V
443ps     1.184V     1.212V     1.146V
542ps     1.207V     1.211V     1.394V
643ps     1.418V     1.233V     1.575V
738ps     1.561V     1.396V     1.682V
857ps     1.67V      1.552V     1.759V
972ps     1.727V     1.638V     1.798V
1.113ns   1.762V     1.693V     1.823V
1.555ns   1.794V     1.742V     1.846V
50ns      1.8V       1.75V      1.85V
[Falling Waveform]
R_fixture= 50.000
V_fixture= 1.800
V_fixture_min= 1.750
V_fixture_max= 1.850
|time   V(typ)   V(min)   V(max)
0s        1.8V       1.75V      1.85V
2.596ns   1.799V     1.748V     1.849V
3.484ns   1.775V     1.723V     1.816V
4.378ns   1.701V     1.661V     1.718V
5.95ns    1.491V     1.487V     1.475V
7.448ns   1.331V     1.345V     1.296V
8.599ns   1.256V     1.28V      1.21V
10.1ns    1.219V     1.246V     1.169V
18.04ns   1.185V     1.212V     1.132V
50ns      1.184V     1.212V     1.13V
[Falling Waveform]
R_fixture= 50.000
V_fixture= 0.0
V_fixture_min= 0.0
V_fixture_max= 0.0
|time   V(typ)   V(min)   V(max)
0s        613.9mV    532.4mV    720.7mV
484ps     614.3mV    532.4mV    706.6mV
524ps     614mV      532.5mV    661.2mV
600ps     588.6mV    533mV      464.8mV
670ps     466.7mV    523.7mV    326.2mV
796ps     253.9mV    379.7mV    181.9mV
986ps     102.9mV    158.2mV    68.33mV
1.225ns   28.46mV    48.2mV     18.26mV
1.556ns   5.093mV    8.821mV    3.279mV
50ns      2.851uV    8.349uV    1.848uV
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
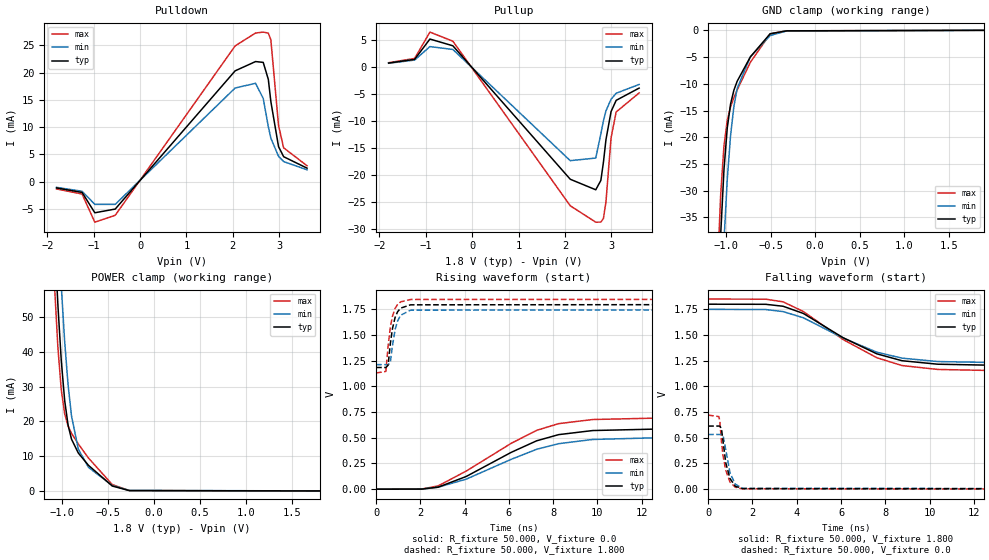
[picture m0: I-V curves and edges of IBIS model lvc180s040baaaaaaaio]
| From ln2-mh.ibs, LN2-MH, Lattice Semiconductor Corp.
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|   Model lvc180s040baaaaaaaio
[Model] lvc180s040baaaaaaaio
Model_type I/O
Polarity   Non-Inverting
Enable   Active-Low
Vinl =  0.630V
Vinh =  1.170V
Vmeas =  0.900V
Cref =  0.0F
Rref =  1.000M
Vref =  0.0V
C_comp   2.000pF   1.500pF   2.500pF
[Temperature Range]   25.000   0.125k   -40.000
[Voltage Range]   1.800V   1.750V   1.850V
[C Comp Corner]
C_comp   2.000pF   1.500pF   2.500pF
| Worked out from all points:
|   slope of the pulldown table from 0 to 0.27 V, typ, clamps not added: 98.3 ohm
|   slope of the pullup table from 0 to 0.27 V, typ, clamps not added: 101 ohm
|   GND clamp passes 1 mA (typ) near -0.54 V on its own axis
|   POWER clamp passes 1 mA (typ) near -0.43 V on its own axis
|   rising waveform, R_fixture 50.000, V_fixture 0.0: 20-80 % time 3.46ns typ, 3.7ns min, 3.46ns max; typ from 0 V to 0.614 V
|   rising waveform, R_fixture 50.000, V_fixture 1.800: 20-80 % time 275ps typ, 283ps min, 269ps max; typ from 1.18 V to 1.8 V
|   falling waveform, R_fixture 50.000, V_fixture 1.800: 20-80 % time 3.16ns typ, 3.25ns min, 3.21ns max; typ from 1.8 V to 1.18 V
|   falling waveform, R_fixture 50.000, V_fixture 0.0: 20-80 % time 293ps typ, 301ps min, 287ps max; typ from 0.614 V to 0 V
[Pulldown]
|Voltage   I(typ)   I(min)   I(max)
-1.8V     -1.176mA   -1.063mA   -1.356mA
-1.25V    -1.992mA   -1.78mA    -2.288mA
-975mV    -5.728mA   -4.186mA   -7.458mA
-535mV    -5.045mA   -4.187mA   -6.188mA
2.05V     20.33mA    17.18mA    24.91mA
2.49V     22.03mA    18.04mA    27.27mA
2.655V    21.88mA    15.26mA    27.44mA
2.765V    18.76mA    10.08mA    27.25mA
2.82V     14.67mA    7.953mA    26mA
2.985V    6.421mA    4.64mA     10.3mA
3.095V    4.566mA    3.671mA    6.195mA
3.6V      2.459mA    2.158mA    2.897mA
[Pullup]
|Voltage   I(typ)   I(min)   I(max)
-1.8V     648.7uA    614uA      713.9uA
-1.24V    1.334mA    1.203mA    1.504mA
-910mV    5.097mA    3.702mA    6.385mA
-415mV    3.846mA    3.17mA     4.694mA
2.115V    -20.86mA   -17.42mA   -25.77mA
2.665V    -22.81mA   -16.93mA   -28.81mA
2.775V    -21.07mA   -12.44mA   -28.79mA
2.83V     -17.73mA   -10.05mA   -28.13mA
2.885V    -13.51mA   -8.193mA   -25.01mA
2.995V    -8.324mA   -6.04mA    -13.17mA
3.105V    -6.251mA   -4.935mA   -8.401mA
3.6V      -3.982mA   -3.308mA   -4.883mA
[GND_clamp]
|Voltage   I(typ)   I(min)   I(max)
-1.8V     -585.7mA   -591.6mA   -585.2mA
-1.097V   -54.7mA    -72.3mA    -45.45mA
-1.06V    -38.22mA   -54.4mA    -30.73mA
-1.023V   -26.05mA   -39.45mA   -21.57mA
-986mV    -18.23mA   -27.86mA   -16.82mA
-949mV    -13.77mA   -19.64mA   -14.3mA
-912mV    -11.21mA   -14.25mA   -12.59mA
-875mV    -9.522mA   -10.86mA   -11.14mA
-727mV    -4.965mA   -4.953mA   -5.98mA
-505mV    -637.4uA   -970.8uA   -651.9uA
-320mV    -95.22uA   -117.2uA   -94.14uA
1.89V     0A         0A         0A
[POWER_clamp]
|Voltage   I(typ)   I(min)   I(max)
-1.789V   650.9mA    666.7mA    643.9mA
-1.086V   73.39mA    99.36mA    59.11mA
-1.049V   53.39mA    77.76mA    41.22mA
-1.012V   37.33mA    58.73mA    28.98mA
-975mV    25.93mA    42.79mA    22.14mA
-938mV    18.88mA    30.44mA    18.64mA
-901mV    14.88mA    21.59mA    16.55mA
-827mV    10.9mA     12.03mA    13.51mA
-716mV    7.349mA    6.765mA    9.446mA
-457mV    1.407mA    1.575mA    1.826mA
-272mV    92.84uA    154.8uA    100.2uA
1.8V      0A         0A         0A
[Ramp]
| variable   typ   min   max
dV/dt_r   0.368/3.473n   0.319/3.729n   0.432/3.460n
dV/dt_f   0.369/3.180n   0.323/3.255n   0.432/3.229n
R_load = 50.000
[Rising Waveform]
R_fixture= 50.000
V_fixture= 0.0
V_fixture_min= 0.0
V_fixture_max= 0.0
|time   V(typ)   V(min)   V(max)
0s        816.5nV    7.287uV    250.2nV
2.059ns   557.2uV    1.734mV    1.47mV
2.801ns   19.27mV    18.74mV    31.42mV
4.07ns    123.2mV    97.18mV    175.6mV
6.109ns   358.5mV    290.6mV    446.4mV
7.256ns   470.6mV    387.9mV    572.3mV
8.25ns    530.7mV    442.7mV    637.7mV
9.791ns   570.5mV    483.7mV    677.8mV
18.17ns   612.3mV    531.2mV    717.8mV
50ns      613.9mV    532.4mV    720.7mV
[Rising Waveform]
R_fixture= 50.000
V_fixture= 1.800
V_fixture_min= 1.750
V_fixture_max= 1.850
|time   V(typ)   V(min)   V(max)
0s        1.184V     1.212V     1.13V
443ps     1.184V     1.212V     1.146V
542ps     1.207V     1.211V     1.394V
643ps     1.418V     1.233V     1.575V
738ps     1.561V     1.396V     1.682V
857ps     1.67V      1.552V     1.759V
972ps     1.727V     1.638V     1.798V
1.113ns   1.762V     1.693V     1.823V
1.557ns   1.794V     1.742V     1.846V
50ns      1.8V       1.75V      1.85V
[Falling Waveform]
R_fixture= 50.000
V_fixture= 1.800
V_fixture_min= 1.750
V_fixture_max= 1.850
|time   V(typ)   V(min)   V(max)
0s        1.8V       1.75V      1.85V
2.597ns   1.799V     1.748V     1.849V
3.385ns   1.78V      1.728V     1.823V
4.298ns   1.71V      1.668V     1.729V
6.095ns   1.474V     1.471V     1.456V
7.618ns   1.317V     1.333V     1.279V
8.755ns   1.25V      1.275V     1.203V
10.37ns   1.216V     1.242V     1.165V
18.04ns   1.185V     1.212V     1.132V
50ns      1.184V     1.212V     1.13V
[Falling Waveform]
R_fixture= 50.000
V_fixture= 0.0
V_fixture_min= 0.0
V_fixture_max= 0.0
|time   V(typ)   V(min)   V(max)
0s        613.9mV    532.4mV    720.7mV
484ps     614.3mV    532.4mV    706.6mV
524ps     614mV      532.5mV    661.1mV
600ps     588.5mV    533mV      464.6mV
670ps     466.6mV    523.7mV    326.1mV
796ps     253.9mV    379.7mV    181.8mV
986ps     102.8mV    158.2mV    68.3mV
1.225ns   28.45mV    48.2mV     18.25mV
1.556ns   5.092mV    8.821mV    3.278mV
50ns      2.851uV    8.349uV    1.848uV
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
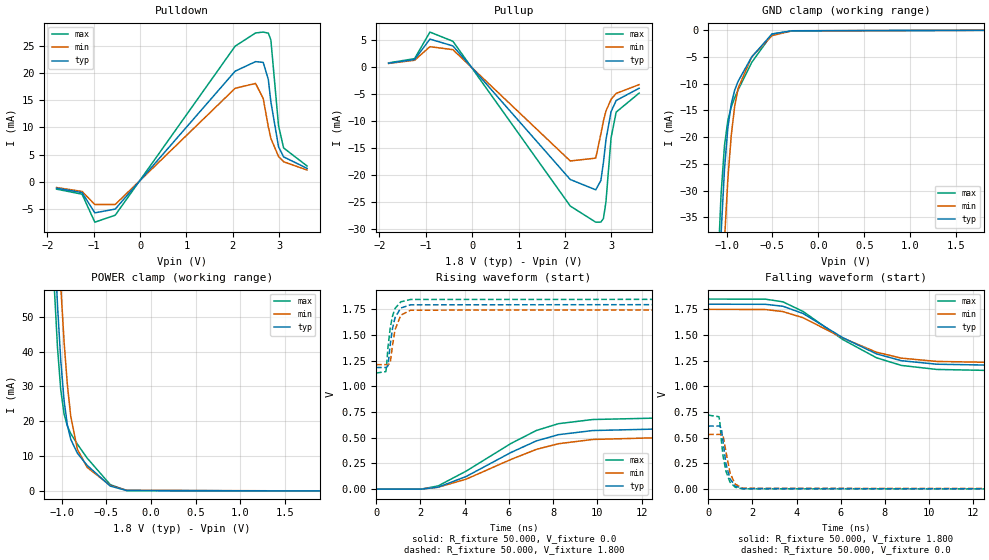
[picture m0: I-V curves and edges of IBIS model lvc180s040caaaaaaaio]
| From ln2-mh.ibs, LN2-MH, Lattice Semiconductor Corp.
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|   Model lvc180s040caaaaaaaio
[Model] lvc180s040caaaaaaaio
Model_type I/O
Polarity   Non-Inverting
Enable   Active-Low
Vinl =  0.630V
Vinh =  1.170V
Vmeas =  0.900V
Cref =  0.0F
Rref =  1.000M
Vref =  0.0V
C_comp   2.000pF   1.500pF   2.500pF
[Temperature Range]   25.000   0.125k   -40.000
[Voltage Range]   1.800V   1.750V   1.850V
[C Comp Corner]
C_comp   2.000pF   1.500pF   2.500pF
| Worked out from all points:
|   slope of the pulldown table from 0 to 0.27 V, typ, clamps not added: 101 ohm
|   slope of the pullup table from 0 to 0.27 V, typ, clamps not added: 98.7 ohm
|   GND clamp passes 1 mA (typ) near -0.53 V on its own axis
|   POWER clamp passes 1 mA (typ) near -0.43 V on its own axis
|   rising waveform, R_fixture 50.000, V_fixture 0.0: 20-80 % time 3.46ns typ, 3.7ns min, 3.46ns max; typ from 0 V to 0.614 V
|   rising waveform, R_fixture 50.000, V_fixture 1.800: 20-80 % time 275ps typ, 283ps min, 269ps max; typ from 1.18 V to 1.8 V
|   falling waveform, R_fixture 50.000, V_fixture 1.800: 20-80 % time 3.15ns typ, 3.25ns min, 3.21ns max; typ from 1.8 V to 1.18 V
|   falling waveform, R_fixture 50.000, V_fixture 0.0: 20-80 % time 293ps typ, 301ps min, 287ps max; typ from 0.614 V to 0 V
[Pulldown]
|Voltage   I(typ)   I(min)   I(max)
-1.8V     -1.169mA   -1.058mA   -1.348mA
-1.25V    -1.982mA   -1.771mA   -2.275mA
-975mV    -5.695mA   -4.164mA   -7.413mA
-535mV    -5.006mA   -4.165mA   -6.129mA
2.05V     20.3mA     17.16mA    24.89mA
2.49V     22.05mA    18.05mA    27.31mA
2.655V    21.91mA    15.27mA    27.47mA
2.765V    18.78mA    10.09mA    27.28mA
2.82V     14.68mA    7.961mA    26.03mA
2.985V    6.428mA    4.644mA    10.31mA
3.095V    4.572mA    3.675mA    6.202mA
3.6V      2.462mA    2.161mA    2.9mA
[Pullup]
|Voltage   I(typ)   I(min)   I(max)
-1.8V     651.5uA    616.3uA    717.1uA
-1.24V    1.339mA    1.207mA    1.511mA
-910mV    5.121mA    3.716mA    6.418mA
-415mV    3.859mA    3.169mA    4.721mA
2.115V    -20.86mA   -17.43mA   -25.77mA
2.665V    -22.77mA   -16.9mA    -28.76mA
2.775V    -21.04mA   -12.42mA   -28.74mA
2.83V     -17.71mA   -10.04mA   -28.08mA
2.885V    -13.49mA   -8.181mA   -24.97mA
2.995V    -8.311mA   -6.031mA   -13.15mA
3.105V    -6.242mA   -4.928mA   -8.389mA
3.6V      -3.975mA   -3.303mA   -4.876mA
[GND_clamp]
|Voltage   I(typ)   I(min)   I(max)
-1.8V     -585.7mA   -591.6mA   -585.2mA
-1.097V   -54.72mA   -72.32mA   -45.47mA
-1.06V    -38.25mA   -54.42mA   -30.77mA
-1.023V   -26.08mA   -39.47mA   -21.61mA
-986mV    -18.26mA   -27.88mA   -16.87mA
-949mV    -13.8mA    -19.67mA   -14.35mA
-912mV    -11.24mA   -14.28mA   -12.64mA
-875mV    -9.559mA   -10.89mA   -11.19mA
-727mV    -5.003mA   -4.98mA    -6.032mA
-505mV    -676uA     -991.2uA   -711.7uA
-283mV    -81.53uA   -80.08uA   -96.55uA
1.8V      0A         0A         0A
[POWER_clamp]
|Voltage   I(typ)   I(min)   I(max)
-1.789V   650.9mA    666.7mA    643.9mA
-1.086V   73.38mA    99.35mA    59.1mA
-1.049V   53.37mA    77.75mA    41.2mA
-1.012V   37.32mA    58.72mA    28.95mA
-975mV    25.91mA    42.78mA    22.11mA
-938mV    18.86mA    30.43mA    18.61mA
-901mV    14.86mA    21.58mA    16.52mA
-827mV    10.88mA    12.01mA    13.47mA
-716mV    7.324mA    6.749mA    9.413mA
-457mV    1.39mA     1.571mA    1.797mA
-272mV    110.1uA    181.7uA    102.9uA
1.89V     0A         0A         0A
[Ramp]
| variable   typ   min   max
dV/dt_r   0.368/3.470n   0.319/3.729n   0.432/3.459n
dV/dt_f   0.369/3.156n   0.323/3.255n   0.432/3.236n
R_load = 50.000
[Rising Waveform]
R_fixture= 50.000
V_fixture= 0.0
V_fixture_min= 0.0
V_fixture_max= 0.0
|time   V(typ)   V(min)   V(max)
0s        816.5nV    7.287uV    250.2nV
2.059ns   557uV      1.734mV    1.468mV
2.801ns   19.27mV    18.74mV    31.41mV
4.07ns    123.2mV    97.18mV    175.6mV
6.103ns   357.8mV    290.1mV    445.7mV
7.25ns    470.1mV    387.4mV    571.7mV
8.241ns   530.3mV    442.3mV    637.3mV
9.791ns   570.5mV    483.7mV    677.8mV
18.03ns   612.1mV    531.1mV    717.6mV
50ns      613.9mV    532.4mV    720.7mV
[Rising Waveform]
R_fixture= 50.000
V_fixture= 1.800
V_fixture_min= 1.750
V_fixture_max= 1.850
|time   V(typ)   V(min)   V(max)
0s        1.184V     1.212V     1.13V
440ps     1.184V     1.212V     1.144V
471ps     1.184V     1.212V     1.195V
539ps     1.203V     1.211V     1.386V
637ps     1.407V     1.228V     1.567V
737ps     1.56V      1.394V     1.681V
857ps     1.67V      1.552V     1.759V
1.115ns   1.763V     1.693V     1.823V
1.557ns   1.794V     1.742V     1.846V
50ns      1.8V       1.75V      1.85V
[Falling Waveform]
R_fixture= 50.000
V_fixture= 1.800
V_fixture_min= 1.750
V_fixture_max= 1.850
|time   V(typ)   V(min)   V(max)
0s        1.8V       1.75V      1.85V
2.594ns   1.799V     1.748V     1.849V
3.383ns   1.78V      1.728V     1.823V
4.298ns   1.709V     1.668V     1.729V
6.093ns   1.474V     1.471V     1.456V
7.614ns   1.317V     1.333V     1.279V
8.747ns   1.25V      1.275V     1.204V
10.35ns   1.216V     1.243V     1.165V
18.66ns   1.185V     1.212V     1.131V
50ns      1.184V     1.212V     1.13V
[Falling Waveform]
R_fixture= 50.000
V_fixture= 0.0
V_fixture_min= 0.0
V_fixture_max= 0.0
|time   V(typ)   V(min)   V(max)
0s        613.9mV    532.4mV    720.7mV
487ps     614.4mV    532.4mV    704.8mV
527ps     613.8mV    532.5mV    655mV
599ps     589.4mV    533mV      467.2mV
672ps     462.2mV    523.1mV    323mV
806ps     242.4mV    362.9mV    173.6mV
986ps     102.8mV    158.3mV    68.3mV
1.22ns    29.23mV    49.5mV     18.75mV
1.559ns   5.019mV    8.695mV    3.231mV
50ns      2.851uV    8.352uV    1.848uV
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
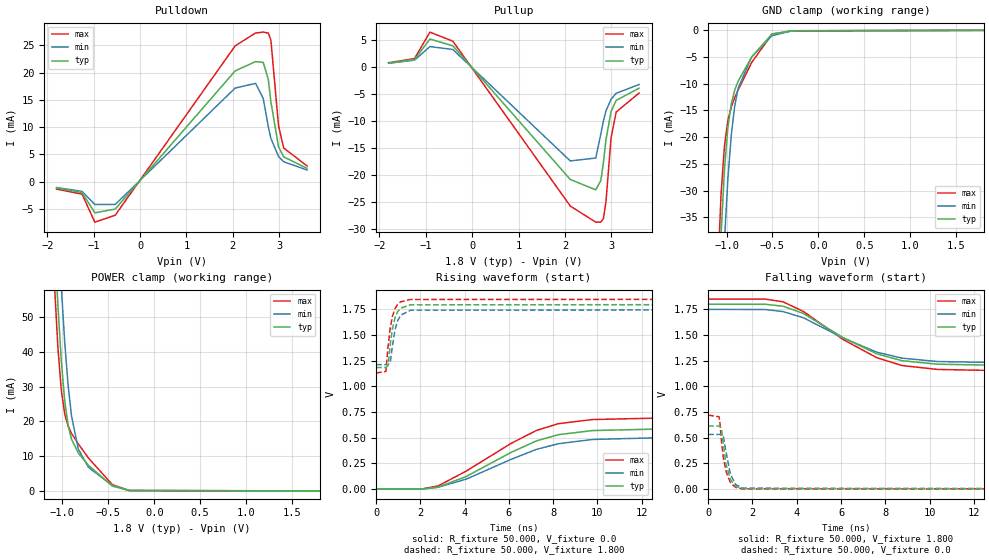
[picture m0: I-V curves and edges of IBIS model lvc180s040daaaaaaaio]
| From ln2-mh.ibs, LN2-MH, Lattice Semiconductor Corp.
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|   Model lvc180s040daaaaaaaio
[Model] lvc180s040daaaaaaaio
Model_type I/O
Polarity   Non-Inverting
Enable   Active-Low
Vinl =  0.630V
Vinh =  1.170V
Vmeas =  0.900V
Cref =  0.0F
Rref =  1.000M
Vref =  0.0V
C_comp   2.000pF   1.500pF   2.500pF
[Temperature Range]   25.000   0.125k   -40.000
[Voltage Range]   1.800V   1.750V   1.850V
[C Comp Corner]
C_comp   2.000pF   1.500pF   2.500pF
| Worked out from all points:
|   slope of the pulldown table from 0 to 0.27 V, typ, clamps not added: 101 ohm
|   slope of the pullup table from 0 to 0.27 V, typ, clamps not added: 101 ohm
|   GND clamp passes 1 mA (typ) near -0.53 V on its own axis
|   POWER clamp passes 1 mA (typ) near -0.43 V on its own axis
|   rising waveform, R_fixture 50.000, V_fixture 0.0: 20-80 % time 3.46ns typ, 3.7ns min, 3.46ns max; typ from 0 V to 0.614 V
|   rising waveform, R_fixture 50.000, V_fixture 1.800: 20-80 % time 275ps typ, 283ps min, 269ps max; typ from 1.18 V to 1.8 V
|   falling waveform, R_fixture 50.000, V_fixture 1.800: 20-80 % time 3.16ns typ, 3.25ns min, 3.21ns max; typ from 1.8 V to 1.18 V
|   falling waveform, R_fixture 50.000, V_fixture 0.0: 20-80 % time 293ps typ, 301ps min, 287ps max; typ from 0.614 V to 0 V
[Pulldown]
|Voltage   I(typ)   I(min)   I(max)
-1.8V     -1.169mA   -1.058mA   -1.348mA
-1.25V    -1.982mA   -1.771mA   -2.275mA
-975mV    -5.695mA   -4.164mA   -7.413mA
-535mV    -5.006mA   -4.165mA   -6.129mA
2.05V     20.33mA    17.18mA    24.91mA
2.49V     22.03mA    18.04mA    27.27mA
2.655V    21.88mA    15.26mA    27.44mA
2.765V    18.76mA    10.08mA    27.25mA
2.82V     14.67mA    7.953mA    26mA
2.985V    6.421mA    4.64mA     10.3mA
3.095V    4.566mA    3.671mA    6.195mA
3.6V      2.459mA    2.158mA    2.897mA
[Pullup]
|Voltage   I(typ)   I(min)   I(max)
-1.8V     648.7uA    614uA      713.9uA
-1.24V    1.334mA    1.203mA    1.504mA
-910mV    5.097mA    3.702mA    6.385mA
-415mV    3.846mA    3.17mA     4.694mA
2.115V    -20.86mA   -17.43mA   -25.77mA
2.665V    -22.77mA   -16.9mA    -28.76mA
2.775V    -21.04mA   -12.42mA   -28.74mA
2.83V     -17.71mA   -10.04mA   -28.08mA
2.885V    -13.49mA   -8.181mA   -24.97mA
2.995V    -8.311mA   -6.031mA   -13.15mA
3.105V    -6.242mA   -4.928mA   -8.389mA
3.6V      -3.975mA   -3.303mA   -4.876mA
[GND_clamp]
|Voltage   I(typ)   I(min)   I(max)
-1.8V     -585.7mA   -591.6mA   -585.2mA
-1.097V   -54.72mA   -72.32mA   -45.47mA
-1.06V    -38.25mA   -54.42mA   -30.77mA
-1.023V   -26.08mA   -39.47mA   -21.61mA
-986mV    -18.26mA   -27.88mA   -16.87mA
-949mV    -13.8mA    -19.67mA   -14.35mA
-912mV    -11.24mA   -14.28mA   -12.64mA
-875mV    -9.559mA   -10.89mA   -11.19mA
-727mV    -5.003mA   -4.98mA    -6.032mA
-505mV    -676uA     -991.2uA   -711.7uA
-283mV    -81.53uA   -80.08uA   -96.55uA
1.8V      -11.32nA   0A         -15.28uA
[POWER_clamp]
|Voltage   I(typ)   I(min)   I(max)
-1.789V   650.9mA    666.7mA    643.9mA
-1.086V   73.39mA    99.36mA    59.11mA
-1.049V   53.39mA    77.76mA    41.22mA
-1.012V   37.33mA    58.73mA    28.98mA
-975mV    25.93mA    42.79mA    22.14mA
-938mV    18.88mA    30.44mA    18.64mA
-901mV    14.88mA    21.59mA    16.55mA
-827mV    10.9mA     12.03mA    13.51mA
-716mV    7.349mA    6.765mA    9.446mA
-457mV    1.407mA    1.575mA    1.826mA
-272mV    92.84uA    154.8uA    100.2uA
1.8V      0A         0A         15.76uA
[Ramp]
| variable   typ   min   max
dV/dt_r   0.368/3.472n   0.319/3.713n   0.432/3.458n
dV/dt_f   0.369/3.159n   0.323/3.255n   0.432/3.224n
R_load = 50.000
[Rising Waveform]
R_fixture= 50.000
V_fixture= 0.0
V_fixture_min= 0.0
V_fixture_max= 0.0
|time   V(typ)   V(min)   V(max)
0s        816.5nV    7.287uV    250.2nV
2.059ns   557.2uV    1.733mV    1.466mV
2.803ns   19.36mV    18.81mV    31.54mV
4.072ns   123.4mV    97.34mV    175.8mV
6.103ns   357.9mV    290.1mV    445.6mV
7.249ns   470mV      387.4mV    571.6mV
8.243ns   530.4mV    442.4mV    637.4mV
9.784ns   570.4mV    483.6mV    677.7mV
18.16ns   612.3mV    531.2mV    717.8mV
50ns      613.9mV    532.4mV    720.7mV
[Rising Waveform]
R_fixture= 50.000
V_fixture= 1.800
V_fixture_min= 1.750
V_fixture_max= 1.850
|time   V(typ)   V(min)   V(max)
0s        1.184V     1.212V     1.13V
443ps     1.184V     1.212V     1.146V
539ps     1.203V     1.211V     1.386V
643ps     1.418V     1.233V     1.575V
737ps     1.56V      1.394V     1.681V
857ps     1.67V      1.552V     1.759V
972ps     1.727V     1.638V     1.798V
1.113ns   1.762V     1.693V     1.823V
1.557ns   1.794V     1.742V     1.846V
50ns      1.8V       1.75V      1.85V
[Falling Waveform]
R_fixture= 50.000
V_fixture= 1.800
V_fixture_min= 1.750
V_fixture_max= 1.850
|time   V(typ)   V(min)   V(max)
0s        1.8V       1.75V      1.85V
2.595ns   1.799V     1.748V     1.849V
3.384ns   1.78V      1.728V     1.823V
4.298ns   1.71V      1.668V     1.729V
6.094ns   1.474V     1.471V     1.456V
7.615ns   1.317V     1.333V     1.279V
8.754ns   1.25V      1.275V     1.203V
10.36ns   1.216V     1.242V     1.165V
18.66ns   1.185V     1.212V     1.131V
50ns      1.184V     1.212V     1.13V
[Falling Waveform]
R_fixture= 50.000
V_fixture= 0.0
V_fixture_min= 0.0
V_fixture_max= 0.0
|time   V(typ)   V(min)   V(max)
0s        613.9mV    532.4mV    720.7mV
487ps     614.4mV    532.4mV    704.8mV
527ps     613.8mV    532.5mV    655mV
599ps     589.4mV    533mV      467.2mV
675ps     455.7mV    522.2mV    318.4mV
806ps     242.4mV    362.7mV    173.6mV
1.003ns   94.11mV    146.4mV    62.13mV
1.236ns   26.81mV    45.51mV    17.19mV
1.555ns   5.118mV    8.864mV    3.293mV
50ns      2.851uV    8.349uV    1.848uV
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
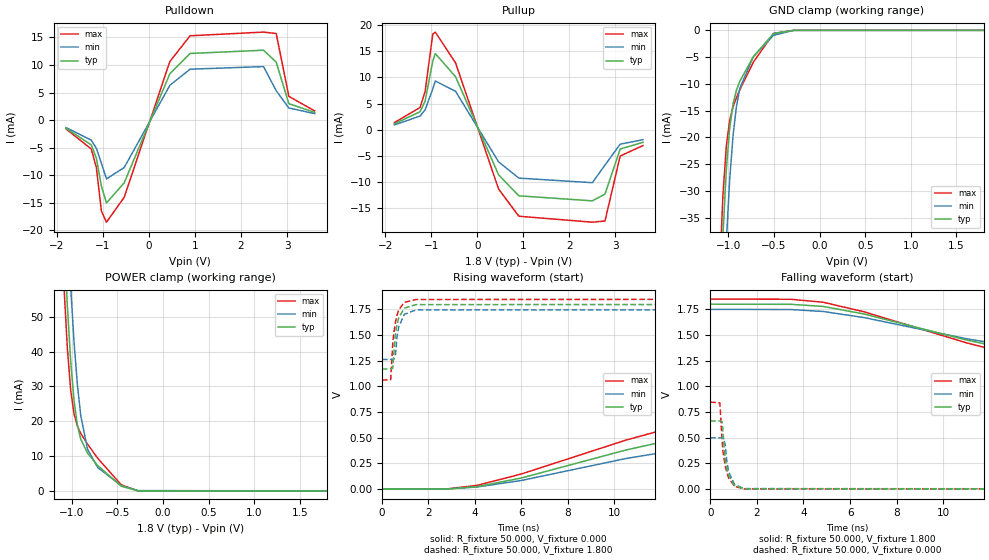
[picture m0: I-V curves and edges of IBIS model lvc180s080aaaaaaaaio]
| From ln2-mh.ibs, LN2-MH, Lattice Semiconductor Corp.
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|   Model lvc180s080aaaaaaaaio
[Model] lvc180s080aaaaaaaaio
Model_type I/O
Polarity   Non-Inverting
Enable   Active-Low
Vinl =  0.630V
Vinh =  1.170V
Vmeas =  0.900V
Cref =  0.0F
Rref =  1.000M
Vref =  0.0V
C_comp   2.000pF   1.500pF   2.500pF
[Temperature Range]   25.000   0.125k   -40.000
[Voltage Range]   1.800V   1.750V   1.850V
[C Comp Corner]
C_comp   2.000pF   1.500pF   2.500pF
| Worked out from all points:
|   slope of the pulldown table from 0 to 0.27 V, typ, clamps not added: 50.5 ohm
|   slope of the pullup table from 0 to 0.27 V, typ, clamps not added: 50.1 ohm
|   GND clamp passes 1 mA (typ) near -0.54 V on its own axis
|   POWER clamp passes 1 mA (typ) near -0.43 V on its own axis
|   rising waveform, R_fixture 50.000, V_fixture 0.000: 20-80 % time 7.22ns typ, 6.95ns min, 7.63ns max; typ from 0 V to 0.664 V
|   rising waveform, R_fixture 50.000, V_fixture 1.800: 20-80 % time 225ps typ, 224ps min, 230ps max; typ from 1.17 V to 1.8 V
|   falling waveform, R_fixture 50.000, V_fixture 1.800: 20-80 % time 7.15ns typ, 6.8ns min, 7.56ns max; typ from 1.8 V to 1.17 V
|   falling waveform, R_fixture 50.000, V_fixture 0.000: 20-80 % time 239ps typ, 237ps min, 244ps max; typ from 0.664 V to 0 V
[Pulldown]
|Voltage   I(typ)   I(min)   I(max)
-1.8V     -1.467mA   -1.347mA   -1.594mA
-1.25V    -4.497mA   -3.644mA   -5.247mA
-1.14V    -6.904mA   -5.119mA   -8.606mA
-1.03V    -11.99mA   -7.86mA    -16.51mA
-920mV    -15.03mA   -10.67mA   -18.53mA
-535mV    -11.38mA   -8.605mA   -14mA
455mV     8.405mA    6.311mA    10.62mA
895mV     12.1mA     9.244mA    15.31mA
2.49V     12.69mA    9.718mA    15.98mA
2.765V    10.53mA    5.338mA    15.72mA
3.04V     2.979mA    2.201mA    4.31mA
3.6V      1.405mA    1.18mA     1.674mA
[Pullup]
|Voltage   I(typ)   I(min)   I(max)
-1.8V     1.12mA     921.8uA    1.36mA
-1.24V    3.446mA    2.621mA    4.254mA
-1.13V    5.497mA    3.816mA    7.346mA
-965mV    13.12mA    7.785mA    18.26mA
-910mV    14.56mA    9.33mA     18.67mA
-470mV    10.14mA    7.355mA    12.79mA
465mV     -8.626mA   -6.147mA   -11.34mA
905mV     -12.63mA   -9.245mA   -16.53mA
2.5V      -13.59mA   -10.12mA   -17.67mA
2.775V    -12.3mA    -6.757mA   -17.44mA
3.105V    -3.679mA   -2.753mA   -5.021mA
3.6V      -2.406mA   -1.897mA   -3.021mA
[GND_clamp]
|Voltage   I(typ)   I(min)   I(max)
-1.8V     -585.7mA   -591.6mA   -585.2mA
-1.097V   -54.7mA    -72.3mA    -45.44mA
-1.06V    -38.22mA   -54.4mA    -30.73mA
-1.023V   -26.04mA   -39.44mA   -21.56mA
-986mV    -18.22mA   -27.85mA   -16.81mA
-949mV    -13.75mA   -19.63mA   -14.29mA
-912mV    -11.19mA   -14.24mA   -12.58mA
-875mV    -9.506mA   -10.84mA   -11.12mA
-727mV    -4.941mA   -4.928mA   -5.958mA
-505mV    -576.1uA   -916.7uA   -589.6uA
-283mV    -824.2nA   -10.84uA   -168.9nA
1.8V      0A         0A         0A
[POWER_clamp]
|Voltage   I(typ)   I(min)   I(max)
-1.789V   650.9mA    666.7mA    643.9mA
-1.086V   73.37mA    99.35mA    59.09mA
-1.049V   53.37mA    77.75mA    41.19mA
-1.012V   37.31mA    58.71mA    28.94mA
-975mV    25.9mA     42.77mA    22.1mA
-938mV    18.85mA    30.42mA    18.6mA
-901mV    14.84mA    21.56mA    16.51mA
-827mV    10.86mA    11.99mA    13.46mA
-716mV    7.305mA    6.728mA    9.397mA
-457mV    1.344mA    1.526mA    1.755mA
-272mV    20.87uA    98.79uA    12.36uA
1.8V      0A         0A         0A
[Ramp]
| variable   typ   min   max
dV/dt_r   0.407/7.233n   0.306/6.985n   0.519/7.653n
dV/dt_f   0.386/7.149n   0.299/6.802n   0.483/7.598n
R_load = 50.000
[Rising Waveform]
R_fixture = 50.000
V_fixture = 0.000
V_fixture_min = 0.000
V_fixture_max = 0.000
|  time   V(typ)   V(min)   V(max)
0s        50.03uV    56.54uV    46.64uV
2.81ns    1.516mV    2.587mV    2.646mV
4.102ns   24.47mV    21.23mV    37.21mV
6.001ns   108.3mV    84.47mV    147.4mV
10.52ns   381.9mV    298.9mV    478.4mV
12.99ns   504.9mV    390mV      631.1mV
15.66ns   593.1mV    453.4mV    744.3mV
18.7ns    648.9mV    491.3mV    816.6mV
21.99ns   663.7mV    498.8mV    846.1mV
50ns      664.2mV    499.2mV    847.8mV
[Rising Waveform]
R_fixture = 50.000
V_fixture = 1.800
V_fixture_min = 1.750
V_fixture_max = 1.850
|  time   V(typ)   V(min)   V(max)
0s        1.169V     1.262V     1.061V
381ps     1.17V      1.262V     1.066V
470ps     1.177V     1.262V     1.419V
509ps     1.3V       1.262V     1.509V
588ps     1.515V     1.312V     1.629V
652ps     1.603V     1.479V     1.694V
730ps     1.672V     1.583V     1.747V
972ps     1.762V     1.702V     1.818V
1.472ns   1.796V     1.744V     1.846V
50ns      1.8V       1.75V      1.85V
[Falling Waveform]
R_fixture = 50.000
V_fixture = 1.800
V_fixture_min = 1.750
V_fixture_max = 1.850
|  time   V(typ)   V(min)   V(max)
0s        1.8V       1.75V      1.85V
3.455ns   1.799V     1.748V     1.848V
4.845ns   1.778V     1.729V     1.819V
6.595ns   1.705V     1.67V      1.726V
10.96ns   1.453V     1.465V     1.426V
13.79ns   1.316V     1.36V      1.26V
16.32ns   1.234V     1.302V     1.156V
19.18ns   1.185V     1.27V      1.089V
23.58ns   1.169V     1.262V     1.061V
50ns      1.169V     1.262V     1.061V
[Falling Waveform]
R_fixture = 50.000
V_fixture = 0.000
V_fixture_min = 0.000
V_fixture_max = 0.000
|  time   V(typ)   V(min)   V(max)
0s        664.2mV    499.2mV    847.8mV
414ps     663.9mV    499.1mV    839.3mV
507ps     657.8mV    498.9mV    479.2mV
555ps     538.6mV    499.7mV    357.5mV
644ps     290.5mV    435.1mV    226.6mV
715ps     199mV      264.9mV    161.4mV
795ps     133.3mV    166.7mV    107.5mV
1.046ns   34.7mV     45.12mV    26.91mV
1.466ns   3.86mV     5.301mV    2.895mV
50ns      50.03uV    56.54uV    46.64uV
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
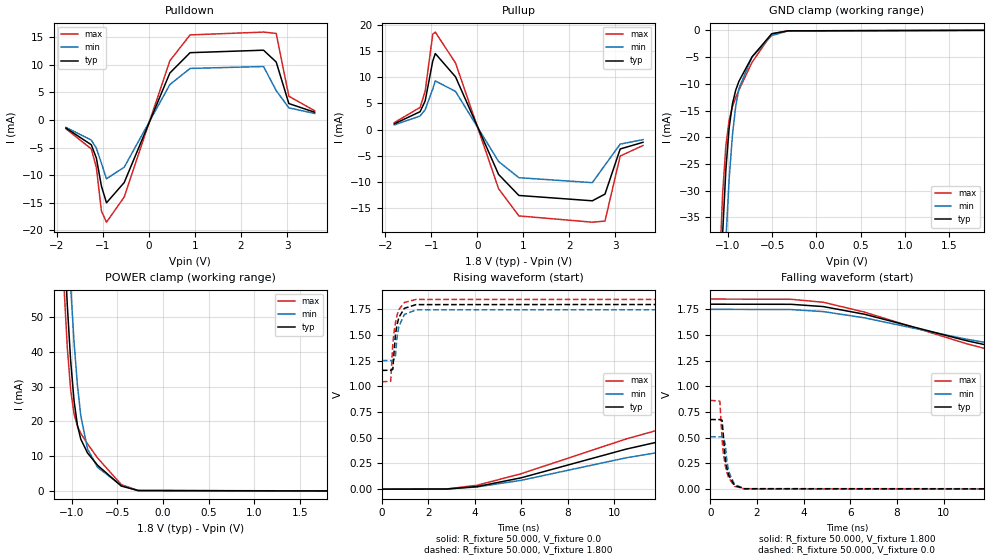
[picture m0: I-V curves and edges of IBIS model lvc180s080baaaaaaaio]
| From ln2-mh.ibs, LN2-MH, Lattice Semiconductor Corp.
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|   Model lvc180s080baaaaaaaio
[Model] lvc180s080baaaaaaaio
Model_type I/O
Polarity   Non-Inverting
Enable   Active-Low
Vinl =  0.630V
Vinh =  1.170V
Vmeas =  0.900V
Cref =  0.0F
Rref =  1.000M
Vref =  0.0V
C_comp   2.000pF   1.500pF   2.500pF
[Temperature Range]   25.000   0.125k   -40.000
[Voltage Range]   1.800V   1.750V   1.850V
[C Comp Corner]
C_comp   2.000pF   1.500pF   2.500pF
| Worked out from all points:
|   slope of the pulldown table from 0 to 0.27 V, typ, clamps not added: 50.5 ohm
|   slope of the pullup table from 0 to 0.27 V, typ, clamps not added: 50.7 ohm
|   GND clamp passes 1 mA (typ) near -0.54 V on its own axis
|   POWER clamp passes 1 mA (typ) near -0.43 V on its own axis
|   rising waveform, R_fixture 50.000, V_fixture 0.0: 20-80 % time 7.22ns typ, 6.95ns min, 7.63ns max; typ from 0 V to 0.678 V
|   rising waveform, R_fixture 50.000, V_fixture 1.800: 20-80 % time 225ps typ, 224ps min, 230ps max; typ from 1.16 V to 1.8 V
|   falling waveform, R_fixture 50.000, V_fixture 1.800: 20-80 % time 7.14ns typ, 6.8ns min, 7.56ns max; typ from 1.8 V to 1.16 V
|   falling waveform, R_fixture 50.000, V_fixture 0.0: 20-80 % time 239ps typ, 237ps min, 244ps max; typ from 0.678 V to 0 V
[Pulldown]
|Voltage   I(typ)   I(min)   I(max)
-1.8V     -1.465mA   -1.345mA   -1.593mA
-1.25V    -4.494mA   -3.64mA    -5.244mA
-1.14V    -6.9mA     -5.114mA   -8.602mA
-1.03V    -11.98mA   -7.851mA   -16.5mA
-920mV    -15.01mA   -10.65mA   -18.52mA
-535mV    -11.33mA   -8.557mA   -13.95mA
455mV     8.497mA    6.404mA    10.71mA
895mV     12.19mA    9.335mA    15.41mA
2.49V     12.64mA    9.682mA    15.92mA
2.765V    10.5mA     5.321mA    15.68mA
3.04V     2.97mA     2.194mA    4.299mA
3.6V      1.402mA    1.177mA    1.669mA
[Pullup]
|Voltage   I(typ)   I(min)   I(max)
-1.8V     1.116mA    918.1uA    1.356mA
-1.24V    3.438mA    2.613mA    4.245mA
-1.13V    5.485mA    3.806mA    7.332mA
-965mV    13.09mA    7.763mA    18.22mA
-910mV    14.53mA    9.303mA    18.62mA
-470mV    10.08mA    7.307mA    12.72mA
465mV     -8.538mA   -6.064mA   -11.25mA
905mV     -12.54mA   -9.153mA   -16.44mA
2.5V      -13.56mA   -10.1mA    -17.64mA
2.775V    -12.28mA   -6.748mA   -17.43mA
3.105V    -3.676mA   -2.75mA    -5.019mA
3.6V      -2.404mA   -1.895mA   -3.019mA
[GND_clamp]
|Voltage   I(typ)   I(min)   I(max)
-1.8V     -585.7mA   -591.6mA   -585.2mA
-1.097V   -54.7mA    -72.3mA    -45.45mA
-1.06V    -38.22mA   -54.4mA    -30.73mA
-1.023V   -26.05mA   -39.45mA   -21.57mA
-986mV    -18.23mA   -27.86mA   -16.82mA
-949mV    -13.77mA   -19.64mA   -14.3mA
-912mV    -11.21mA   -14.25mA   -12.59mA
-875mV    -9.522mA   -10.86mA   -11.14mA
-727mV    -4.965mA   -4.953mA   -5.98mA
-505mV    -637.4uA   -970.8uA   -651.9uA
-320mV    -95.22uA   -117.2uA   -94.14uA
1.89V     0A         0A         0A
[POWER_clamp]
|Voltage   I(typ)   I(min)   I(max)
-1.789V   650.9mA    666.7mA    643.9mA
-1.086V   73.39mA    99.36mA    59.11mA
-1.049V   53.39mA    77.76mA    41.22mA
-1.012V   37.33mA    58.73mA    28.98mA
-975mV    25.93mA    42.79mA    22.14mA
-938mV    18.88mA    30.44mA    18.64mA
-901mV    14.88mA    21.59mA    16.55mA
-827mV    10.9mA     12.03mA    13.51mA
-716mV    7.349mA    6.765mA    9.446mA
-457mV    1.407mA    1.575mA    1.826mA
-272mV    92.84uA    154.8uA    100.2uA
1.8V      0A         0A         0A
[Ramp]
| variable   typ   min   max
dV/dt_r   0.407/7.235n   0.306/6.992n   0.519/7.648n
dV/dt_f   0.386/7.157n   0.299/6.803n   0.483/7.569n
R_load = 50.000
[Rising Waveform]
R_fixture= 50.000
V_fixture= 0.0
V_fixture_min= 0.0
V_fixture_max= 0.0
|time   V(typ)   V(min)   V(max)
0s        848.9nV    8.122uV    251.1nV
2.805ns   1.461mV    2.555mV    2.601mV
4.102ns   24.91mV    21.61mV    37.93mV
6.002ns   110.5mV    86.17mV    150.5mV
10.52ns   389.6mV    305mV      488.2mV
12.99ns   515.2mV    398mV      644.2mV
15.66ns   605.1mV    462.6mV    759.5mV
18.7ns    662mV      501.3mV    833.3mV
22.01ns   677.1mV    508.9mV    863.4mV
50ns      677.6mV    509.4mV    865.1mV
[Rising Waveform]
R_fixture= 50.000
V_fixture= 1.800
V_fixture_min= 1.750
V_fixture_max= 1.850
|time   V(typ)   V(min)   V(max)
0s        1.156V     1.252V     1.045V
381ps     1.157V     1.252V     1.05V
472ps     1.166V     1.253V     1.416V
509ps     1.29V      1.253V     1.502V
588ps     1.509V     1.303V     1.624V
653ps     1.6V       1.476V     1.692V
733ps     1.671V     1.583V     1.747V
969ps     1.76V      1.7V       1.817V
1.473ns   1.796V     1.745V     1.846V
50ns      1.8V       1.75V      1.85V
[Falling Waveform]
R_fixture= 50.000
V_fixture= 1.800
V_fixture_min= 1.750
V_fixture_max= 1.850
|time   V(typ)   V(min)   V(max)
0s        1.8V       1.75V      1.85V
3.455ns   1.799V     1.748V     1.848V
4.845ns   1.777V     1.728V     1.819V
6.594ns   1.703V     1.668V     1.724V
10.96ns   1.446V     1.46V      1.417V
13.78ns   1.306V     1.352V     1.249V
16.29ns   1.223V     1.293V     1.143V
19.16ns   1.172V     1.26V      1.074V
23.31ns   1.157V     1.252V     1.045V
50ns      1.156V     1.252V     1.045V
[Falling Waveform]
R_fixture= 50.000
V_fixture= 0.0
V_fixture_min= 0.0
V_fixture_max= 0.0
|time   V(typ)   V(min)   V(max)
0s        677.5mV    509.3mV    864.9mV
414ps     677.2mV    509.1mV    856.1mV
507ps     671mV      509mV      488.5mV
555ps     549.4mV    509.8mV    364.5mV
645ps     294.5mV    441.3mV    229.9mV
714ps     204mV      271.9mV    165.3mV
795ps     136mV      170mV      109.6mV
1.043ns   35.93mV    46.7mV     27.86mV
1.465ns   3.909mV    5.385mV    2.922mV
50ns      3.049uV    9.341uV    1.915uV
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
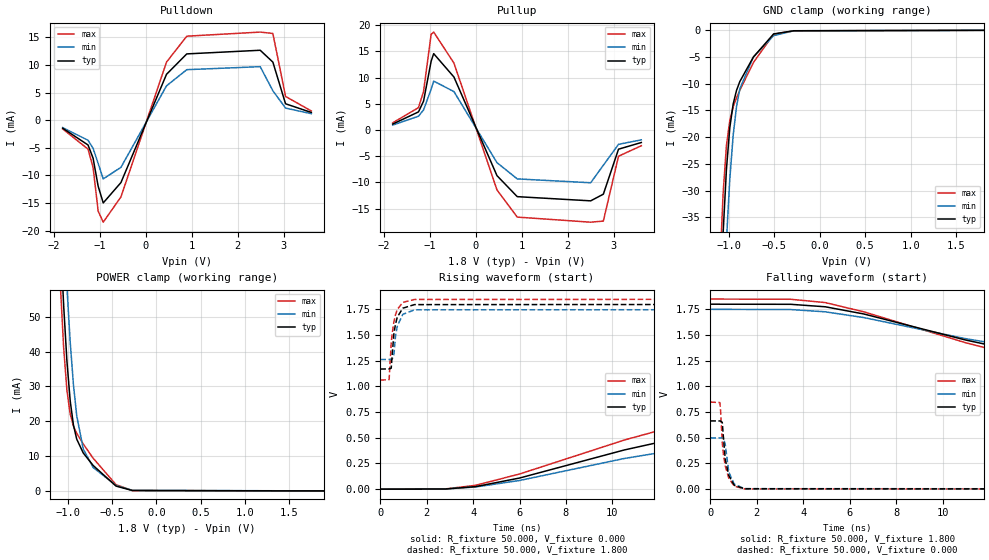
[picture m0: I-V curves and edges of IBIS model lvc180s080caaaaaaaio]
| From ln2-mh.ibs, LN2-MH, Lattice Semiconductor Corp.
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|   Model lvc180s080caaaaaaaio
[Model] lvc180s080caaaaaaaio
Model_type I/O
Polarity   Non-Inverting
Enable   Active-Low
Vinl =  0.630V
Vinh =  1.170V
Vmeas =  0.900V
Cref =  0.0F
Rref =  1.000M
Vref =  0.0V
C_comp   2.000pF   1.500pF   2.500pF
[Temperature Range]   25.000   0.125k   -40.000
[Voltage Range]   1.800V   1.750V   1.850V
[C Comp Corner]
C_comp   2.000pF   1.500pF   2.500pF
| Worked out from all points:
|   slope of the pulldown table from 0 to 0.27 V, typ, clamps not added: 51.1 ohm
|   slope of the pullup table from 0 to 0.27 V, typ, clamps not added: 50.1 ohm
|   GND clamp passes 1 mA (typ) near -0.53 V on its own axis
|   POWER clamp passes 1 mA (typ) near -0.43 V on its own axis
|   rising waveform, R_fixture 50.000, V_fixture 0.000: 20-80 % time 7.22ns typ, 6.95ns min, 7.63ns max; typ from 0 V to 0.664 V
|   rising waveform, R_fixture 50.000, V_fixture 1.800: 20-80 % time 225ps typ, 224ps min, 230ps max; typ from 1.17 V to 1.8 V
|   falling waveform, R_fixture 50.000, V_fixture 1.800: 20-80 % time 7.14ns typ, 6.8ns min, 7.56ns max; typ from 1.8 V to 1.17 V
|   falling waveform, R_fixture 50.000, V_fixture 0.000: 20-80 % time 239ps typ, 237ps min, 244ps max; typ from 0.664 V to 0 V
[Pulldown]
|Voltage   I(typ)   I(min)   I(max)
-1.8V     -1.459mA   -1.34mA    -1.585mA
-1.25V    -4.484mA   -3.631mA   -5.231mA
-1.14V    -6.884mA   -5.102mA   -8.582mA
-1.03V    -11.95mA   -7.833mA   -16.46mA
-920mV    -14.98mA   -10.63mA   -18.47mA
-535mV    -11.29mA   -8.534mA   -13.89mA
455mV     8.318mA    6.228mA    10.53mA
895mV     12.01mA    9.153mA    15.22mA
2.49V     12.67mA    9.698mA    15.96mA
2.765V    10.52mA    5.33mA     15.71mA
3.04V     2.976mA    2.198mA    4.308mA
3.6V      1.404mA    1.179mA    1.673mA
[Pullup]
|Voltage   I(typ)   I(min)   I(max)
-1.8V     1.119mA    920.4uA    1.359mA
-1.24V    3.443mA    2.618mA    4.252mA
-1.13V    5.493mA    3.812mA    7.343mA
-965mV    13.11mA    7.776mA    18.25mA
-910mV    14.55mA    9.318mA    18.66mA
-470mV    10.09mA    7.312mA    12.75mA
465mV     -8.717mA   -6.238mA   -11.44mA
905mV     -12.72mA   -9.335mA   -16.62mA
2.5V      -13.52mA   -10.07mA   -17.59mA
2.775V    -12.25mA   -6.73mA    -17.38mA
3.105V    -3.667mA   -2.742mA   -5.006mA
3.6V      -2.398mA   -1.89mA    -3.012mA
[GND_clamp]
|Voltage   I(typ)   I(min)   I(max)
-1.8V     -585.7mA   -591.6mA   -585.2mA
-1.097V   -54.72mA   -72.32mA   -45.47mA
-1.06V    -38.25mA   -54.42mA   -30.77mA
-1.023V   -26.08mA   -39.47mA   -21.61mA
-986mV    -18.26mA   -27.88mA   -16.87mA
-949mV    -13.8mA    -19.67mA   -14.35mA
-912mV    -11.24mA   -14.28mA   -12.64mA
-875mV    -9.559mA   -10.89mA   -11.19mA
-727mV    -5.003mA   -4.98mA    -6.032mA
-505mV    -676uA     -991.2uA   -711.7uA
-283mV    -81.53uA   -80.08uA   -96.55uA
1.8V      0A         0A         0A
[POWER_clamp]
|Voltage   I(typ)   I(min)   I(max)
-1.789V   650.9mA    666.7mA    643.9mA
-1.086V   73.38mA    99.35mA    59.1mA
-1.049V   53.37mA    77.75mA    41.2mA
-1.012V   37.32mA    58.72mA    28.95mA
-975mV    25.91mA    42.78mA    22.11mA
-938mV    18.86mA    30.43mA    18.61mA
-901mV    14.86mA    21.58mA    16.52mA
-827mV    10.88mA    12.01mA    13.47mA
-716mV    7.324mA    6.749mA    9.413mA
-457mV    1.39mA     1.571mA    1.797mA
-272mV    110.1uA    181.7uA    102.9uA
1.89V     0A         0A         0A
[Ramp]
| variable   typ   min   max
dV/dt_r   0.407/7.233n   0.306/6.991n   0.519/7.655n
dV/dt_f   0.386/7.153n   0.299/6.811n   0.483/7.577n
R_load = 50.000
[Rising Waveform]
R_fixture = 50.000
V_fixture = 0.000
V_fixture_min = 0.000
V_fixture_max = 0.000
|  time   V(typ)   V(min)   V(max)
0s        104.4uV    53.23uV    92.55uV
2.81ns    1.572mV    2.583mV    2.692mV
4.102ns   24.53mV    21.23mV    37.26mV
6.002ns   108.4mV    84.51mV    147.6mV
10.52ns   381.9mV    298.9mV    478.4mV
12.99ns   505.1mV    390.1mV    631.3mV
15.66ns   593.1mV    453.4mV    744.3mV
18.7ns    648.9mV    491.3mV    816.6mV
21.99ns   663.7mV    498.7mV    846.1mV
50ns      664.2mV    499.2mV    847.8mV
[Rising Waveform]
R_fixture = 50.000
V_fixture = 1.800
V_fixture_min = 1.750
V_fixture_max = 1.850
|  time   V(typ)   V(min)   V(max)
0s        1.169V     1.262V     1.061V
381ps     1.17V      1.262V     1.066V
472ps     1.178V     1.262V     1.424V
509ps     1.3V       1.262V     1.509V
588ps     1.514V     1.312V     1.629V
653ps     1.604V     1.481V     1.695V
733ps     1.674V     1.586V     1.749V
969ps     1.761V     1.701V     1.818V
1.473ns   1.796V     1.745V     1.846V
50ns      1.8V       1.75V      1.85V
[Falling Waveform]
R_fixture = 50.000
V_fixture = 1.800
V_fixture_min = 1.750
V_fixture_max = 1.850
|  time   V(typ)   V(min)   V(max)
0s        1.8V       1.75V      1.85V
3.456ns   1.799V     1.748V     1.848V
4.936ns   1.775V     1.726V     1.816V
6.596ns   1.705V     1.67V      1.726V
10.96ns   1.452V     1.465V     1.426V
13.78ns   1.316V     1.36V      1.261V
16.28ns   1.235V     1.302V     1.157V
19.38ns   1.183V     1.269V     1.086V
23.32ns   1.169V     1.262V     1.061V
50ns      1.169V     1.262V     1.061V
[Falling Waveform]
R_fixture = 50.000
V_fixture = 0.000
V_fixture_min = 0.000
V_fixture_max = 0.000
|  time   V(typ)   V(min)   V(max)
0s        664.2mV    499.2mV    847.8mV
410ps     663.9mV    499.1mV    842.8mV
439ps     664.1mV    499.1mV    779.7mV
515ps     650.2mV    499mV      454.5mV
563ps     507.1mV    499.9mV    342mV
645ps     288.8mV    432.6mV    225.4mV
794ps     134.1mV    167.6mV    108.1mV
1.03ns    37.89mV    49.09mV    29.42mV
1.469ns   3.858mV    5.223mV    2.897mV
50ns      104.4uV    53.23uV    92.55uV
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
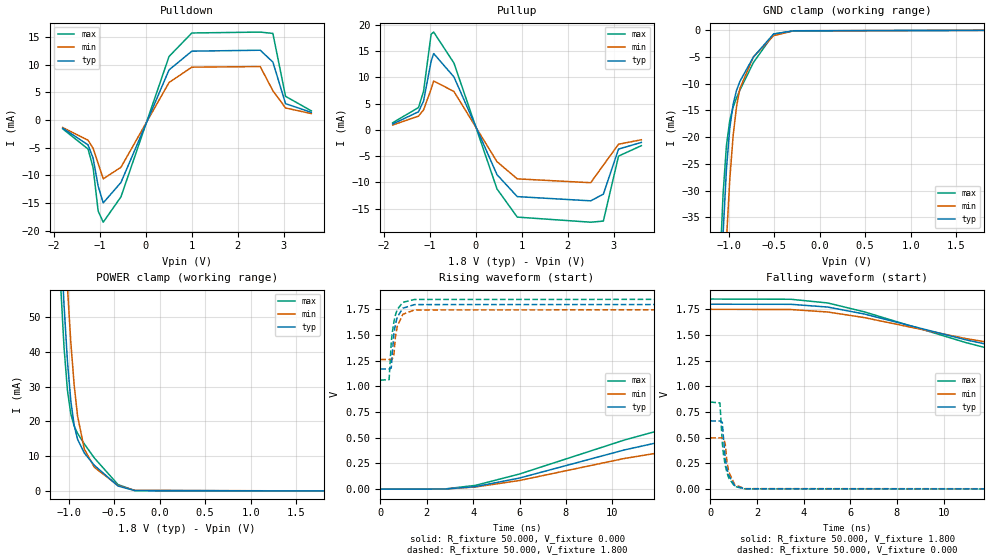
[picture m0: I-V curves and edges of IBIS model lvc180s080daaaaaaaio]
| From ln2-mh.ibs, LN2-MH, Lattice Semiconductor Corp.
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|   Model lvc180s080daaaaaaaio
[Model] lvc180s080daaaaaaaio
Model_type I/O
Polarity   Non-Inverting
Enable   Active-Low
Vinl =  0.630V
Vinh =  1.170V
Vmeas =  0.900V
Cref =  0.0F
Rref =  1.000M
Vref =  0.0V
C_comp   2.000pF   1.500pF   2.500pF
[Temperature Range]   25.000   0.125k   -40.000
[Voltage Range]   1.800V   1.750V   1.850V
[C Comp Corner]
C_comp   2.000pF   1.500pF   2.500pF
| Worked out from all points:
|   slope of the pulldown table from 0 to 0.27 V, typ, clamps not added: 51.1 ohm
|   slope of the pullup table from 0 to 0.27 V, typ, clamps not added: 50.7 ohm
|   GND clamp passes 1 mA (typ) near -0.53 V on its own axis
|   POWER clamp passes 1 mA (typ) near -0.43 V on its own axis
|   rising waveform, R_fixture 50.000, V_fixture 0.000: 20-80 % time 7.22ns typ, 6.95ns min, 7.63ns max; typ from 0 V to 0.664 V
|   rising waveform, R_fixture 50.000, V_fixture 1.800: 20-80 % time 225ps typ, 224ps min, 230ps max; typ from 1.17 V to 1.8 V
|   falling waveform, R_fixture 50.000, V_fixture 1.800: 20-80 % time 7.14ns typ, 6.8ns min, 7.56ns max; typ from 1.8 V to 1.17 V
|   falling waveform, R_fixture 50.000, V_fixture 0.000: 20-80 % time 239ps typ, 237ps min, 244ps max; typ from 0.664 V to 0 V
[Pulldown]
|Voltage   I(typ)   I(min)   I(max)
-1.8V     -1.459mA   -1.34mA    -1.585mA
-1.25V    -4.484mA   -3.631mA   -5.231mA
-1.14V    -6.884mA   -5.102mA   -8.582mA
-1.03V    -11.95mA   -7.833mA   -16.46mA
-920mV    -14.98mA   -10.63mA   -18.47mA
-535mV    -11.29mA   -8.534mA   -13.89mA
510mV     9.082mA    6.802mA    11.51mA
1.005V    12.47mA    9.575mA    15.76mA
2.49V     12.64mA    9.682mA    15.92mA
2.765V    10.5mA     5.321mA    15.68mA
3.04V     2.97mA     2.194mA    4.299mA
3.6V      1.402mA    1.177mA    1.669mA
[Pullup]
|Voltage   I(typ)   I(min)   I(max)
-1.8V     1.116mA    918.1uA    1.356mA
-1.24V    3.438mA    2.613mA    4.245mA
-1.13V    5.485mA    3.806mA    7.332mA
-965mV    13.09mA    7.763mA    18.22mA
-910mV    14.53mA    9.303mA    18.62mA
-470mV    10.08mA    7.307mA    12.72mA
465mV     -8.538mA   -6.064mA   -11.25mA
905mV     -12.72mA   -9.335mA   -16.62mA
2.5V      -13.52mA   -10.07mA   -17.59mA
2.775V    -12.25mA   -6.73mA    -17.38mA
3.105V    -3.667mA   -2.742mA   -5.006mA
3.6V      -2.398mA   -1.89mA    -3.012mA
[GND_clamp]
|Voltage   I(typ)   I(min)   I(max)
-1.8V     -585.7mA   -591.6mA   -585.2mA
-1.097V   -54.72mA   -72.32mA   -45.47mA
-1.06V    -38.25mA   -54.42mA   -30.77mA
-1.023V   -26.08mA   -39.47mA   -21.61mA
-986mV    -18.26mA   -27.88mA   -16.87mA
-949mV    -13.8mA    -19.67mA   -14.35mA
-912mV    -11.24mA   -14.28mA   -12.64mA
-875mV    -9.559mA   -10.89mA   -11.19mA
-727mV    -5.003mA   -4.98mA    -6.032mA
-505mV    -676uA     -991.2uA   -711.7uA
-283mV    -81.53uA   -80.08uA   -96.55uA
1.8V      -11.32nA   0A         -15.28uA
[POWER_clamp]
|Voltage   I(typ)   I(min)   I(max)
-1.789V   650.9mA    666.7mA    643.9mA
-1.086V   73.39mA    99.36mA    59.11mA
-1.049V   53.39mA    77.76mA    41.22mA
-1.012V   37.33mA    58.73mA    28.98mA
-975mV    25.93mA    42.79mA    22.14mA
-938mV    18.88mA    30.44mA    18.64mA
-901mV    14.88mA    21.59mA    16.55mA
-827mV    10.9mA     12.03mA    13.51mA
-716mV    7.349mA    6.765mA    9.446mA
-457mV    1.407mA    1.575mA    1.826mA
-272mV    92.84uA    154.8uA    100.2uA
1.8V      0A         0A         15.76uA
[Ramp]
| variable   typ   min   max
dV/dt_r   0.407/7.233n   0.306/6.975n   0.519/7.648n
dV/dt_f   0.386/7.161n   0.299/6.802n   0.483/7.573n
R_load = 50.000
[Rising Waveform]
R_fixture = 50.000
V_fixture = 0.000
V_fixture_min = 0.000
V_fixture_max = 0.000
|  time   V(typ)   V(min)   V(max)
0s        104.4uV    53.23uV    92.55uV
2.804ns   1.529mV    2.542mV    2.631mV
4.102ns   24.52mV    21.23mV    37.26mV
6.002ns   108.4mV    84.5mV     147.6mV
10.52ns   381.9mV    298.9mV    478.4mV
12.99ns   504.9mV    390mV      631.1mV
15.66ns   593.1mV    453.4mV    744.3mV
18.7ns    648.9mV    491.3mV    816.6mV
21.99ns   663.7mV    498.7mV    846.1mV
50ns      664.2mV    499.2mV    847.8mV
[Rising Waveform]
R_fixture = 50.000
V_fixture = 1.800
V_fixture_min = 1.750
V_fixture_max = 1.850
|  time   V(typ)   V(min)   V(max)
0s        1.169V     1.262V     1.061V
381ps     1.17V      1.262V     1.066V
472ps     1.178V     1.262V     1.424V
509ps     1.3V       1.262V     1.509V
588ps     1.514V     1.312V     1.629V
653ps     1.604V     1.481V     1.695V
733ps     1.674V     1.586V     1.749V
969ps     1.761V     1.701V     1.818V
1.473ns   1.796V     1.744V     1.846V
50ns      1.8V       1.75V      1.85V
[Falling Waveform]
R_fixture = 50.000
V_fixture = 1.800
V_fixture_min = 1.750
V_fixture_max = 1.850
|  time   V(typ)   V(min)   V(max)
0s        1.8V       1.75V      1.85V
3.455ns   1.799V     1.748V     1.848V
5.035ns   1.772V     1.724V     1.812V
6.595ns   1.705V     1.67V      1.726V
10.96ns   1.453V     1.465V     1.426V
13.78ns   1.316V     1.36V      1.261V
16.31ns   1.234V     1.302V     1.156V
19.17ns   1.185V     1.27V      1.089V
23.32ns   1.169V     1.262V     1.061V
50ns      1.169V     1.262V     1.061V
[Falling Waveform]
R_fixture = 50.000
V_fixture = 0.000
V_fixture_min = 0.000
V_fixture_max = 0.000
|  time   V(typ)   V(min)   V(max)
0s        664.2mV    499.2mV    847.8mV
414ps     663.9mV    499.1mV    839.3mV
515ps     650.2mV    499mV      454.3mV
564ps     503.2mV    499.9mV    340.1mV
645ps     288.8mV    432.8mV    225.4mV
714ps     200.1mV    266.7mV    162.2mV
795ps     133.4mV    166.7mV    107.5mV
1.047ns   34.57mV    44.9mV     26.79mV
1.465ns   3.933mV    5.324mV    2.955mV
50ns      104.4uV    53.23uV    92.55uV
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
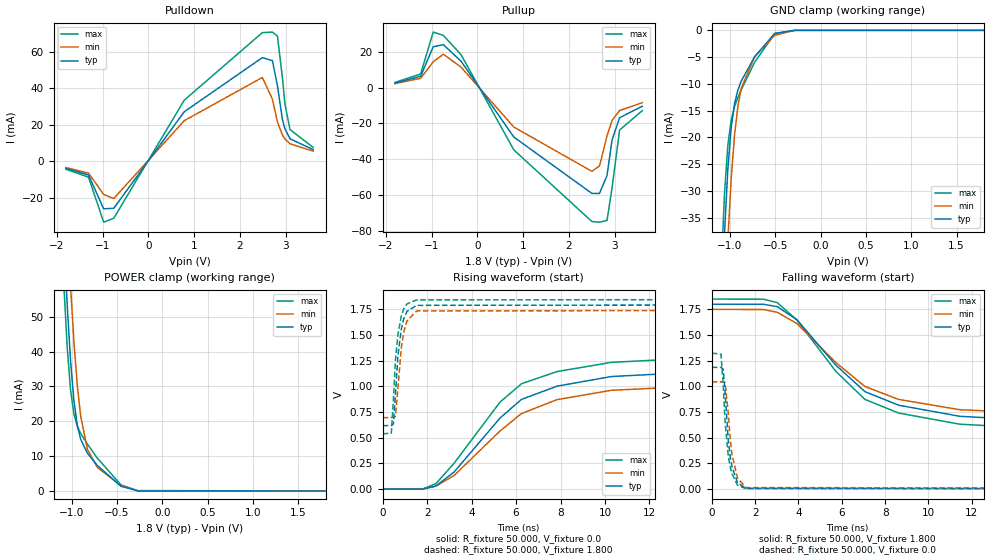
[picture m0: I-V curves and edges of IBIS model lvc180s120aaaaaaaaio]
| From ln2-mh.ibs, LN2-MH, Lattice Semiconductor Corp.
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|   Model lvc180s120aaaaaaaaio
[Model] lvc180s120aaaaaaaaio
Model_type I/O
Polarity   Non-Inverting
Enable   Active-Low
Vinl =  0.630V
Vinh =  1.170V
Vmeas =  0.900V
Cref =  0.0F
Rref =  1.000M
Vref =  0.0V
C_comp   2.000pF   1.500pF   2.500pF
[Temperature Range]   25.000   0.125k   -40.000
[Voltage Range]   1.800V   1.750V   1.850V
[C Comp Corner]
C_comp   2.000pF   1.500pF   2.500pF
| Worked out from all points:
|   slope of the pulldown table from 0 to 0.27 V, typ, clamps not added: 25.5 ohm
|   slope of the pullup table from 0 to 0.27 V, typ, clamps not added: 25.4 ohm
|   GND clamp passes 1 mA (typ) near -0.54 V on its own axis
|   POWER clamp passes 1 mA (typ) near -0.43 V on its own axis
|   rising waveform, R_fixture 50.000, V_fixture 0.0: 20-80 % time 3.49ns typ, 3.66ns min, 3.31ns max; typ from 0 V to 1.19 V
|   rising waveform, R_fixture 50.000, V_fixture 1.800: 20-80 % time 287ps typ, 298ps min, 278ps max; typ from 0.618 V to 1.8 V
|   falling waveform, R_fixture 50.000, V_fixture 1.800: 20-80 % time 3.72ns typ, 3.75ns min, 3.59ns max; typ from 1.8 V to 0.618 V
|   falling waveform, R_fixture 50.000, V_fixture 0.0: 20-80 % time 304ps typ, 320ps min, 292ps max; typ from 1.19 V to 0 V
[Pulldown]
|Voltage   I(typ)   I(min)   I(max)
-1.8V     -3.877mA   -3.515mA   -4.389mA
-1.305V   -7.584mA   -6.516mA   -8.753mA
-975mV    -26.06mA   -18.23mA   -33.39mA
-755mV    -25.77mA   -20.44mA   -31.26mA
785mV     27.08mA    22.18mA    33.4mA
2.49V     56.7mA     45.84mA    70.38mA
2.71V     55.03mA    33.97mA    70.68mA
2.82V     41.23mA    21.45mA    68.45mA
2.93V     22.68mA    14.26mA    45.39mA
2.985V    17.62mA    12.18mA    30.98mA
3.095V    12.25mA    9.529mA    17.31mA
3.6V      6.356mA    5.498mA    7.532mA
[Pullup]
|Voltage   I(typ)   I(min)   I(max)
-1.8V     2.451mA    2.174mA    2.834mA
-1.24V    6.317mA    5.145mA    7.596mA
-965mV    22.76mA    14.37mA    30.95mA
-745mV    23.94mA    18.6mA     29.12mA
-360mV    14.78mA    11.46mA    18.43mA
795mV     -27.66mA   -22.07mA   -34.81mA
2.5V      -59.12mA   -46.8mA    -74.84mA
2.665V    -59.16mA   -43.79mA   -75.19mA
2.83V     -49.17mA   -27mA      -74.24mA
2.94V     -29.33mA   -18.37mA   -56.01mA
3.105V    -16.86mA   -12.83mA   -23.74mA
3.6V      -10.43mA   -8.491mA   -12.93mA
[GND_clamp]
|Voltage   I(typ)   I(min)   I(max)
-1.8V     -585.7mA   -591.6mA   -585.2mA
-1.097V   -54.7mA    -72.3mA    -45.44mA
-1.06V    -38.22mA   -54.4mA    -30.73mA
-1.023V   -26.04mA   -39.44mA   -21.56mA
-986mV    -18.22mA   -27.85mA   -16.81mA
-949mV    -13.75mA   -19.63mA   -14.29mA
-912mV    -11.19mA   -14.24mA   -12.58mA
-875mV    -9.506mA   -10.84mA   -11.12mA
-727mV    -4.941mA   -4.928mA   -5.958mA
-505mV    -576.1uA   -916.7uA   -589.6uA
-283mV    -824.2nA   -10.84uA   -168.9nA
1.8V      0A         0A         0A
[POWER_clamp]
|Voltage   I(typ)   I(min)   I(max)
-1.789V   650.9mA    666.7mA    643.9mA
-1.086V   73.37mA    99.35mA    59.09mA
-1.049V   53.37mA    77.75mA    41.19mA
-1.012V   37.31mA    58.71mA    28.94mA
-975mV    25.9mA     42.77mA    22.1mA
-938mV    18.85mA    30.42mA    18.6mA
-901mV    14.84mA    21.56mA    16.51mA
-827mV    10.86mA    11.99mA    13.46mA
-716mV    7.305mA    6.728mA    9.397mA
-457mV    1.344mA    1.526mA    1.755mA
-272mV    20.87uA    98.79uA    12.36uA
1.8V      0A         0A         0A
[Ramp]
| variable   typ   min   max
dV/dt_r   0.711/3.496n   0.627/3.664n   0.794/3.311n
dV/dt_f   0.709/3.718n   0.632/3.774n   0.787/3.594n
R_load = 50.000
[Rising Waveform]
R_fixture= 50.000
V_fixture= 0.0
V_fixture_min= 0.0
V_fixture_max= 0.0
|time   V(typ)   V(min)   V(max)
0s        239.2nV    2.446uV    65.57nV
1.805ns   909.2uV    1.933mV    2.26mV
2.395ns   30.51mV    30.27mV    53.66mV
3.215ns   167mV      133.2mV    252.7mV
5.276ns   691.5mV    565.5mV    846.3mV
6.245ns   873.6mV    736.1mV    1.026V
7.836ns   1.002V     870.8mV    1.144V
10.28ns   1.096V     962mV      1.234V
18.13ns   1.184V     1.044V     1.32V
50ns      1.185V     1.045V     1.324V
[Rising Waveform]
R_fixture= 50.000
V_fixture= 1.800
V_fixture_min= 1.750
V_fixture_max= 1.850
|time   V(typ)   V(min)   V(max)
0s        618mV      696mV      538.5mV
391ps     619.2mV    696.7mV    545.1mV
484ps     634mV      697.3mV    870.8mV
579ps     928.9mV    710.9mV    1.266V
687ps     1.299V     978.6mV    1.504V
836ps     1.552V     1.374V     1.683V
947ps     1.657V     1.526V     1.755V
1.091ns   1.729V     1.637V     1.802V
1.529ns   1.789V     1.734V     1.842V
50ns      1.8V       1.75V      1.85V
[Falling Waveform]
R_fixture= 50.000
V_fixture= 1.800
V_fixture_min= 1.750
V_fixture_max= 1.850
|time   V(typ)   V(min)   V(max)
0s        1.8V       1.75V      1.85V
2.387ns   1.799V     1.748V     1.849V
3.026ns   1.776V     1.721V     1.815V
3.927ns   1.65V      1.612V     1.646V
5.716ns   1.209V     1.234V     1.149V
7.067ns   949.4mV    999.6mV    873.7mV
8.617ns   817.3mV    873.8mV    741.1mV
11.45ns   709mV      773mV      632.2mV
19.38ns   620.3mV    697.5mV    542.3mV
50ns      618mV      696mV      538.5mV
[Falling Waveform]
R_fixture= 50.000
V_fixture= 0.0
V_fixture_min= 0.0
V_fixture_max= 0.0
|time   V(typ)   V(min)   V(max)
0s        1.185V     1.045V     1.324V
425ps     1.185V     1.045V     1.314V
527ps     1.168V     1.045V     1.022V
617ps     936.2mV    1.037V     650mV
761ps     479.9mV    742.5mV    324.6mV
856ps     309.2mV    482.7mV    213.1mV
935ps     218.3mV    334.3mV    149.6mV
1.187ns   63.4mV     108.5mV    38.8mV
1.569ns   8.645mV    15.41mV    5.44mV
50ns      851.7nV    2.861uV    485.5nV
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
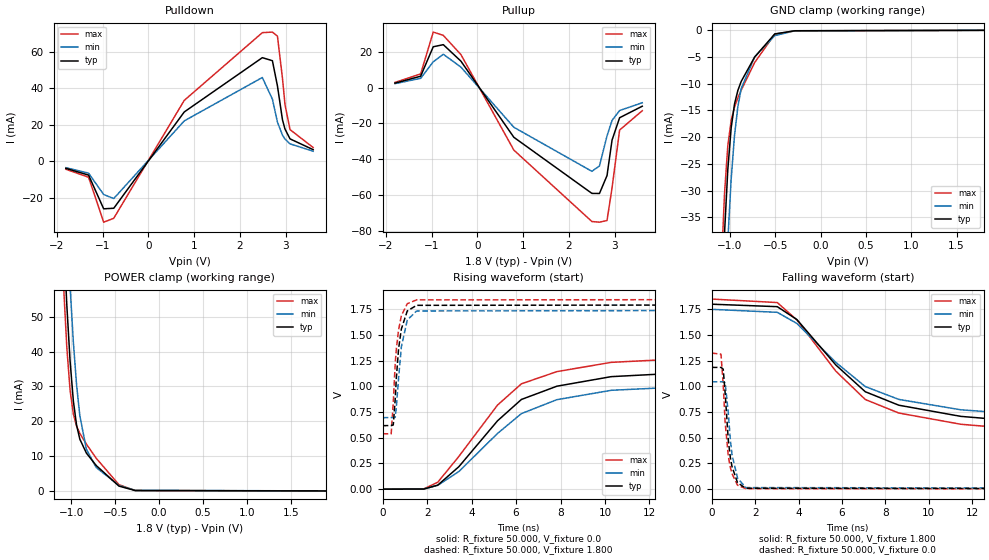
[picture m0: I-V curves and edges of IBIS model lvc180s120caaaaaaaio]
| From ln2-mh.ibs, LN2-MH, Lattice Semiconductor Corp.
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|   Model lvc180s120caaaaaaaio
[Model] lvc180s120caaaaaaaio
Model_type I/O
Polarity   Non-Inverting
Enable   Active-Low
Vinl =  0.630V
Vinh =  1.170V
Vmeas =  0.900V
Cref =  0.0F
Rref =  1.000M
Vref =  0.0V
C_comp   2.000pF   1.500pF   2.500pF
[Temperature Range]   25.000   0.125k   -40.000
[Voltage Range]   1.800V   1.750V   1.850V
[C Comp Corner]
C_comp   2.000pF   1.500pF   2.500pF
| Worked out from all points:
|   slope of the pulldown table from 0 to 0.27 V, typ, clamps not added: 25.7 ohm
|   slope of the pullup table from 0 to 0.27 V, typ, clamps not added: 25.4 ohm
|   GND clamp passes 1 mA (typ) near -0.53 V on its own axis
|   POWER clamp passes 1 mA (typ) near -0.43 V on its own axis
|   rising waveform, R_fixture 50.000, V_fixture 0.0: 20-80 % time 3.49ns typ, 3.66ns min, 3.31ns max; typ from 0 V to 1.19 V
|   rising waveform, R_fixture 50.000, V_fixture 1.800: 20-80 % time 287ps typ, 298ps min, 278ps max; typ from 0.618 V to 1.8 V
|   falling waveform, R_fixture 50.000, V_fixture 1.800: 20-80 % time 3.72ns typ, 3.75ns min, 3.59ns max; typ from 1.8 V to 0.618 V
|   falling waveform, R_fixture 50.000, V_fixture 0.0: 20-80 % time 304ps typ, 320ps min, 292ps max; typ from 1.19 V to 0 V
[Pulldown]
|Voltage   I(typ)   I(min)   I(max)
-1.8V     -3.87mA    -3.507mA   -4.38mA
-1.305V   -7.572mA   -6.505mA   -8.74mA
-975mV    -26.01mA   -18.2mA    -33.33mA
-755mV    -25.71mA   -20.39mA   -31.19mA
785mV     26.98mA    22.09mA    33.31mA
2.49V     56.68mA    45.82mA    70.36mA
2.71V     55.01mA    33.96mA    70.67mA
2.82V     41.23mA    21.45mA    68.44mA
2.93V     22.68mA    14.25mA    45.39mA
2.985V    17.62mA    12.17mA    30.98mA
3.095V    12.25mA    9.527mA    17.31mA
3.6V      6.355mA    5.497mA    7.531mA
[Pullup]
|Voltage   I(typ)   I(min)   I(max)
-1.8V     2.45mA     2.173mA    2.833mA
-1.24V    6.314mA    5.142mA    7.594mA
-965mV    22.75mA    14.36mA    30.94mA
-745mV    23.92mA    18.58mA    29.1mA
-360mV    14.71mA    11.4mA     18.36mA
795mV     -27.75mA   -22.16mA   -34.9mA
2.5V      -59.06mA   -46.75mA   -74.76mA
2.665V    -59.11mA   -43.75mA   -75.13mA
2.83V     -49.14mA   -26.98mA   -74.18mA
2.94V     -29.31mA   -18.35mA   -55.98mA
3.105V    -16.85mA   -12.82mA   -23.73mA
3.6V      -10.42mA   -8.484mA   -12.92mA
[GND_clamp]
|Voltage   I(typ)   I(min)   I(max)
-1.8V     -585.7mA   -591.6mA   -585.2mA
-1.097V   -54.72mA   -72.32mA   -45.47mA
-1.06V    -38.25mA   -54.42mA   -30.77mA
-1.023V   -26.08mA   -39.47mA   -21.61mA
-986mV    -18.26mA   -27.88mA   -16.87mA
-949mV    -13.8mA    -19.67mA   -14.35mA
-912mV    -11.24mA   -14.28mA   -12.64mA
-875mV    -9.559mA   -10.89mA   -11.19mA
-727mV    -5.003mA   -4.98mA    -6.032mA
-505mV    -676uA     -991.2uA   -711.7uA
-283mV    -81.53uA   -80.08uA   -96.55uA
1.8V      0A         0A         0A
[POWER_clamp]
|Voltage   I(typ)   I(min)   I(max)
-1.789V   650.9mA    666.7mA    643.9mA
-1.086V   73.38mA    99.35mA    59.1mA
-1.049V   53.37mA    77.75mA    41.2mA
-1.012V   37.32mA    58.72mA    28.95mA
-975mV    25.91mA    42.78mA    22.11mA
-938mV    18.86mA    30.43mA    18.61mA
-901mV    14.86mA    21.58mA    16.52mA
-827mV    10.88mA    12.01mA    13.47mA
-716mV    7.324mA    6.749mA    9.413mA
-457mV    1.39mA     1.571mA    1.797mA
-272mV    110.1uA    181.7uA    102.9uA
1.89V     0A         0A         0A
[Ramp]
| variable   typ   min   max
dV/dt_r   0.711/3.505n   0.627/3.669n   0.794/3.312n
dV/dt_f   0.709/3.718n   0.632/3.757n   0.787/3.593n
R_load = 50.000
[Rising Waveform]
R_fixture= 50.000
V_fixture= 0.0
V_fixture_min= 0.0
V_fixture_max= 0.0
|time   V(typ)   V(min)   V(max)
0s        239.2nV    2.446uV    65.57nV
1.86ns    1.375mV    2.999mV    3.783mV
2.48ns    39.33mV    37.34mV    67.59mV
3.426ns   218.2mV    171.2mV    318.2mV
5.165ns   665mV      542.2mV    818.2mV
6.24ns    872.9mV    735.4mV    1.025V
7.836ns   1.002V     870.9mV    1.144V
10.28ns   1.095V     962.1mV    1.234V
18.13ns   1.184V     1.044V     1.32V
50ns      1.185V     1.045V     1.324V
[Rising Waveform]
R_fixture= 50.000
V_fixture= 1.800
V_fixture_min= 1.750
V_fixture_max= 1.850
|time   V(typ)   V(min)   V(max)
0s        618mV      696mV      538.5mV
384ps     619.2mV    696.6mV    539mV
478ps     624.7mV    697.2mV    842.5mV
566ps     877.9mV    698.9mV    1.225V
616ps     1.081V     799.7mV    1.365V
717ps     1.367V     1.081V     1.549V
842ps     1.559V     1.385V     1.688V
1.107ns   1.734V     1.646V     1.805V
1.529ns   1.789V     1.734V     1.842V
50ns      1.8V       1.75V      1.85V
[Falling Waveform]
R_fixture= 50.000
V_fixture= 1.800
V_fixture_min= 1.750
V_fixture_max= 1.850
|time   V(typ)   V(min)   V(max)
0s        1.8V       1.75V      1.85V
3.02ns    1.776V     1.721V     1.816V
3.927ns   1.65V      1.612V     1.646V
5.716ns   1.209V     1.234V     1.149V
7.076ns   948.1mV    998.4mV    872.5mV
8.624ns   816.9mV    873.4mV    740.7mV
11.48ns   708.4mV    772.4mV    631.7mV
15.06ns   645.3mV    717mV      568.7mV
20.05ns   619.3mV    696.9mV    540.6mV
50ns      618mV      696mV      538.5mV
[Falling Waveform]
R_fixture= 50.000
V_fixture= 0.0
V_fixture_min= 0.0
V_fixture_max= 0.0
|time   V(typ)   V(min)   V(max)
0s        1.185V     1.045V     1.324V
425ps     1.185V     1.045V     1.314V
527ps     1.168V     1.045V     1.022V
617ps     936.2mV    1.037V     650mV
761ps     479.9mV    742.5mV    324.6mV
856ps     309.2mV    482.7mV    213.1mV
935ps     218.3mV    334.3mV    149.6mV
1.188ns   63.06mV    108mV      38.58mV
1.567ns   8.729mV    15.56mV    5.491mV
50ns      851.9nV    2.86uV     488.6nV
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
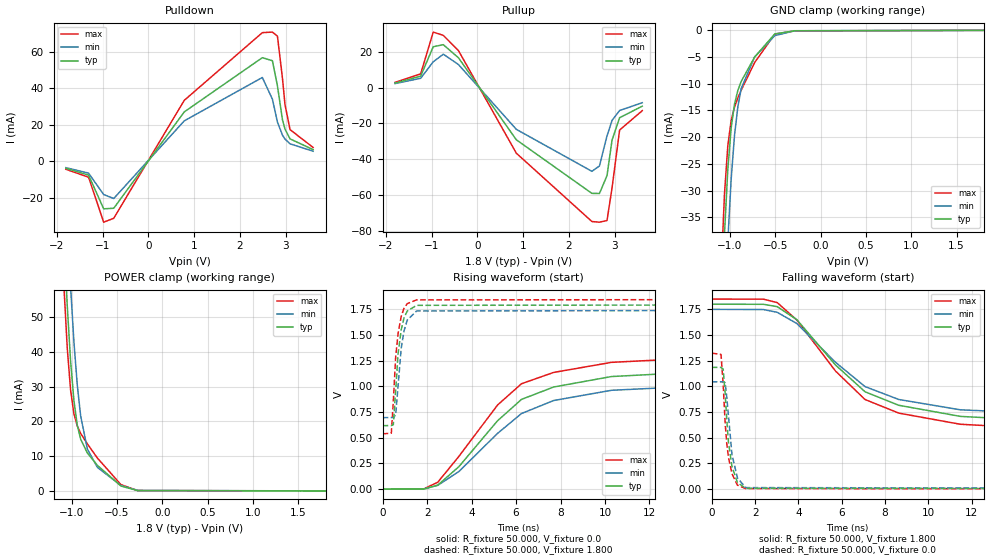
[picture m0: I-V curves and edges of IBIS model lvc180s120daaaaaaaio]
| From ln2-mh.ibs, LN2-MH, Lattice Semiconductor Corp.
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|   Model lvc180s120daaaaaaaio
[Model] lvc180s120daaaaaaaio
Model_type I/O
Polarity   Non-Inverting
Enable   Active-Low
Vinl =  0.630V
Vinh =  1.170V
Vmeas =  0.900V
Cref =  0.0F
Rref =  1.000M
Vref =  0.0V
C_comp   2.000pF   1.500pF   2.500pF
[Temperature Range]   25.000   0.125k   -40.000
[Voltage Range]   1.800V   1.750V   1.850V
[C Comp Corner]
C_comp   2.000pF   1.500pF   2.500pF
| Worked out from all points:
|   slope of the pulldown table from 0 to 0.27 V, typ, clamps not added: 25.7 ohm
|   slope of the pullup table from 0 to 0.27 V, typ, clamps not added: 25.6 ohm
|   GND clamp passes 1 mA (typ) near -0.53 V on its own axis
|   POWER clamp passes 1 mA (typ) near -0.43 V on its own axis
|   rising waveform, R_fixture 50.000, V_fixture 0.0: 20-80 % time 3.49ns typ, 3.66ns min, 3.31ns max; typ from 0 V to 1.19 V
|   rising waveform, R_fixture 50.000, V_fixture 1.800: 20-80 % time 287ps typ, 298ps min, 278ps max; typ from 0.618 V to 1.8 V
|   falling waveform, R_fixture 50.000, V_fixture 1.800: 20-80 % time 3.72ns typ, 3.75ns min, 3.6ns max; typ from 1.8 V to 0.618 V
|   falling waveform, R_fixture 50.000, V_fixture 0.0: 20-80 % time 304ps typ, 320ps min, 292ps max; typ from 1.19 V to 0 V
[Pulldown]
|Voltage   I(typ)   I(min)   I(max)
-1.8V     -3.87mA    -3.507mA   -4.38mA
-1.305V   -7.572mA   -6.505mA   -8.74mA
-975mV    -26.01mA   -18.2mA    -33.33mA
-755mV    -25.71mA   -20.39mA   -31.19mA
785mV     26.98mA    22.09mA    33.31mA
2.49V     56.65mA    45.81mA    70.33mA
2.71V     54.99mA    33.94mA    70.64mA
2.82V     41.21mA    21.44mA    68.41mA
2.93V     22.67mA    14.25mA    45.37mA
2.985V    17.61mA    12.17mA    30.97mA
3.095V    12.24mA    9.523mA    17.3mA
3.6V      6.353mA    5.495mA    7.528mA
[Pullup]
|Voltage   I(typ)   I(min)   I(max)
-1.8V     2.448mA    2.171mA    2.83mA
-1.24V    6.309mA    5.137mA    7.587mA
-965mV    22.73mA    14.35mA    30.91mA
-745mV    23.89mA    18.57mA    29.07mA
-415mV    16.59mA    12.83mA    20.61mA
850mV     -29.17mA   -23.35mA   -36.65mA
2.5V      -59.06mA   -46.75mA   -74.76mA
2.665V    -59.11mA   -43.75mA   -75.13mA
2.83V     -49.14mA   -26.98mA   -74.18mA
2.94V     -29.31mA   -18.35mA   -55.98mA
3.105V    -16.85mA   -12.82mA   -23.73mA
3.6V      -10.42mA   -8.484mA   -12.92mA
[GND_clamp]
|Voltage   I(typ)   I(min)   I(max)
-1.8V     -585.7mA   -591.6mA   -585.2mA
-1.097V   -54.72mA   -72.32mA   -45.47mA
-1.06V    -38.25mA   -54.42mA   -30.77mA
-1.023V   -26.08mA   -39.47mA   -21.61mA
-986mV    -18.26mA   -27.88mA   -16.87mA
-949mV    -13.8mA    -19.67mA   -14.35mA
-912mV    -11.24mA   -14.28mA   -12.64mA
-875mV    -9.559mA   -10.89mA   -11.19mA
-727mV    -5.003mA   -4.98mA    -6.032mA
-505mV    -676uA     -991.2uA   -711.7uA
-283mV    -81.53uA   -80.08uA   -96.55uA
1.8V      -11.32nA   0A         -15.28uA
[POWER_clamp]
|Voltage   I(typ)   I(min)   I(max)
-1.789V   650.9mA    666.7mA    643.9mA
-1.086V   73.39mA    99.36mA    59.11mA
-1.049V   53.39mA    77.76mA    41.22mA
-1.012V   37.33mA    58.73mA    28.98mA
-975mV    25.93mA    42.79mA    22.14mA
-938mV    18.88mA    30.44mA    18.64mA
-901mV    14.88mA    21.59mA    16.55mA
-827mV    10.9mA     12.03mA    13.51mA
-716mV    7.349mA    6.765mA    9.446mA
-457mV    1.407mA    1.575mA    1.826mA
-272mV    92.84uA    154.8uA    100.2uA
1.8V      0A         0A         15.76uA
[Ramp]
| variable   typ   min   max
dV/dt_r   0.711/3.499n   0.627/3.666n   0.794/3.312n
dV/dt_f   0.709/3.718n   0.632/3.747n   0.787/3.593n
R_load = 50.000
[Rising Waveform]
R_fixture= 50.000
V_fixture= 0.0
V_fixture_min= 0.0
V_fixture_max= 0.0
|time   V(typ)   V(min)   V(max)
0s        239.2nV    2.446uV    65.57nV
1.86ns    1.377mV    2.998mV    3.783mV
2.48ns    39.34mV    37.34mV    67.59mV
3.427ns   218.5mV    171.4mV    318.5mV
5.166ns   665.4mV    542.4mV    818.5mV
6.245ns   873.6mV    736.1mV    1.026V
7.689ns   994mV      862.6mV    1.136V
10.29ns   1.096V     962.2mV    1.234V
18.09ns   1.184V     1.044V     1.32V
50ns      1.185V     1.045V     1.324V
[Rising Waveform]
R_fixture= 50.000
V_fixture= 1.800
V_fixture_min= 1.750
V_fixture_max= 1.850
|time   V(typ)   V(min)   V(max)
0s        618mV      696mV      538.5mV
391ps     619.2mV    696.7mV    545.1mV
480ps     627.2mV    697.2mV    851.9mV
586ps     958.6mV    721.7mV    1.286V
696ps     1.321V     1.009V     1.518V
835ps     1.551V     1.372V     1.682V
962ps     1.667V     1.541V     1.761V
1.108ns   1.734V     1.646V     1.806V
1.529ns   1.789V     1.734V     1.842V
50ns      1.8V       1.75V      1.85V
[Falling Waveform]
R_fixture= 50.000
V_fixture= 1.800
V_fixture_min= 1.750
V_fixture_max= 1.850
|time   V(typ)   V(min)   V(max)
0s        1.8V       1.75V      1.85V
2.387ns   1.799V     1.748V     1.849V
3.022ns   1.776V     1.721V     1.816V
3.927ns   1.65V      1.612V     1.646V
5.717ns   1.208V     1.234V     1.149V
7.077ns   948mV      998.3mV    872.6mV
8.637ns   816.3mV    872.7mV    740.1mV
11.48ns   708.3mV    772.3mV    631.6mV
19.39ns   620.3mV    697.5mV    542.3mV
50ns      618mV      696mV      538.5mV
[Falling Waveform]
R_fixture= 50.000
V_fixture= 0.0
V_fixture_min= 0.0
V_fixture_max= 0.0
|time   V(typ)   V(min)   V(max)
0s        1.185V     1.045V     1.324V
427ps     1.185V     1.045V     1.311V
527ps     1.168V     1.045V     1.022V
617ps     936.2mV    1.037V     649.9mV
686ps     699.3mV    909.4mV    459.1mV
769ps     461.7mV    719.8mV    313.2mV
935ps     218.3mV    334.3mV    149.6mV
1.187ns   63.4mV     108.5mV    38.8mV
1.57ns    8.604mV    15.33mV    5.418mV
50ns      853.4nV    2.861uV    485.8nV
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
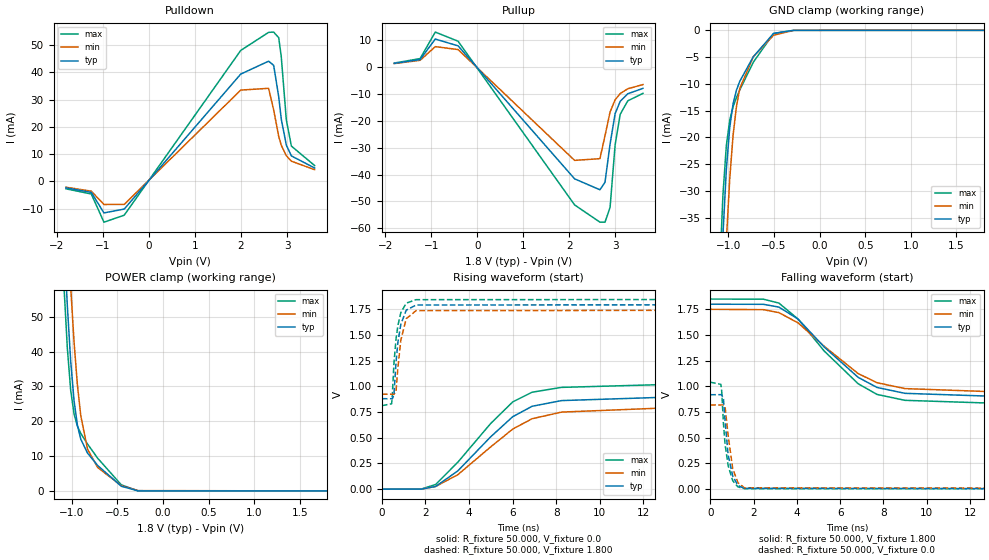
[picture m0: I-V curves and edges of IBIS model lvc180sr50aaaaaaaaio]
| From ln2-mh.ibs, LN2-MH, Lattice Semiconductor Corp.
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|   Model lvc180sr50aaaaaaaaio
[Model] lvc180sr50aaaaaaaaio
Model_type I/O
Polarity   Non-Inverting
Enable   Active-Low
Vinl =  0.630V
Vinh =  1.170V
Vmeas =  0.900V
Cref =  0.0F
Rref =  1.000M
Vref =  0.0V
C_comp   2.000pF   1.500pF   2.500pF
[Temperature Range]   25.000   0.125k   -40.000
[Voltage Range]   1.800V   1.750V   1.850V
[C Comp Corner]
C_comp   2.000pF   1.500pF   2.500pF
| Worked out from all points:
|   slope of the pulldown table from 0 to 0.27 V, typ, clamps not added: 49.6 ohm
|   slope of the pullup table from 0 to 0.27 V, typ, clamps not added: 49.6 ohm
|   GND clamp passes 1 mA (typ) near -0.54 V on its own axis
|   POWER clamp passes 1 mA (typ) near -0.43 V on its own axis
|   rising waveform, R_fixture 50.000, V_fixture 0.0: 20-80 % time 2.69ns typ, 2.94ns min, 2.63ns max; typ from 0 V to 0.919 V
|   rising waveform, R_fixture 50.000, V_fixture 1.800: 20-80 % time 283ps typ, 290ps min, 279ps max; typ from 0.881 V to 1.8 V
|   falling waveform, R_fixture 50.000, V_fixture 1.800: 20-80 % time 2.75ns typ, 2.86ns min, 2.76ns max; typ from 1.8 V to 0.881 V
|   falling waveform, R_fixture 50.000, V_fixture 0.0: 20-80 % time 297ps typ, 306ps min, 288ps max; typ from 0.919 V to 0 V
[Pulldown]
|Voltage   I(typ)   I(min)   I(max)
-1.8V     -2.363mA   -2.137mA   -2.722mA
-1.25V    -4.032mA   -3.596mA   -4.637mA
-975mV    -11.57mA   -8.474mA   -14.98mA
-535mV    -10.16mA   -8.453mA   -12.41mA
1.995V    39.39mA    33.51mA    48.07mA
2.6V      44.12mA    34.16mA    54.7mA
2.71V     42.6mA     26.25mA    54.8mA
2.82V     31.06mA    16.51mA    52.73mA
2.875V    22.88mA    13.26mA    45.79mA
2.985V    13.32mA    9.433mA    22.58mA
3.095V    9.348mA    7.405mA    12.96mA
3.6V      4.909mA    4.29mA     5.793mA
[Pullup]
|Voltage   I(typ)   I(min)   I(max)
-1.8V     1.312mA    1.24mA     1.445mA
-1.24V    2.721mA    2.444mA    3.082mA
-910mV    10.35mA    7.536mA    12.94mA
-415mV    7.828mA    6.445mA    9.541mA
2.115V    -41.6mA    -34.74mA   -51.29mA
2.665V    -45.66mA   -34.1mA    -57.69mA
2.775V    -42.89mA   -25.6mA    -57.71mA
2.885V    -28.74mA   -16.79mA   -52.24mA
2.995V    -17.38mA   -12.23mA   -28.99mA
3.105V    -12.79mA   -9.915mA   -17.63mA
3.27V     -9.975mA   -8.121mA   -12.61mA
3.6V      -7.975mA   -6.563mA   -9.828mA
[GND_clamp]
|Voltage   I(typ)   I(min)   I(max)
-1.8V     -585.7mA   -591.6mA   -585.2mA
-1.097V   -54.7mA    -72.3mA    -45.44mA
-1.06V    -38.22mA   -54.4mA    -30.73mA
-1.023V   -26.04mA   -39.44mA   -21.56mA
-986mV    -18.22mA   -27.85mA   -16.81mA
-949mV    -13.75mA   -19.63mA   -14.29mA
-912mV    -11.19mA   -14.24mA   -12.58mA
-875mV    -9.506mA   -10.84mA   -11.12mA
-727mV    -4.941mA   -4.928mA   -5.958mA
-505mV    -576.1uA   -916.7uA   -589.6uA
-283mV    -824.2nA   -10.84uA   -168.9nA
1.8V      0A         0A         0A
[POWER_clamp]
|Voltage   I(typ)   I(min)   I(max)
-1.789V   650.9mA    666.7mA    643.9mA
-1.086V   73.37mA    99.35mA    59.09mA
-1.049V   53.37mA    77.75mA    41.19mA
-1.012V   37.31mA    58.71mA    28.94mA
-975mV    25.9mA     42.77mA    22.1mA
-938mV    18.85mA    30.42mA    18.6mA
-901mV    14.84mA    21.56mA    16.51mA
-827mV    10.86mA    11.99mA    13.46mA
-716mV    7.305mA    6.728mA    9.397mA
-457mV    1.344mA    1.526mA    1.755mA
-272mV    20.87uA    98.79uA    12.36uA
1.8V      0A         0A         0A
[Ramp]
| variable   typ   min   max
dV/dt_r   0.551/2.699n   0.492/2.940n   0.624/2.632n
dV/dt_f   0.552/2.765n   0.496/2.863n   0.623/2.784n
R_load = 50.000
[Rising Waveform]
R_fixture= 50.000
V_fixture= 0.0
V_fixture_min= 0.0
V_fixture_max= 0.0
|time   V(typ)   V(min)   V(max)
0s        367.3nV    3.507uV    105.1nV
1.819ns   617.1uV    1.357mV    1.516mV
2.469ns   26.41mV    26.42mV    45.74mV
3.489ns   178.1mV    140.9mV    262.4mV
4.991ns   508.4mV    410.5mV    637.8mV
6.011ns   705.6mV    585.3mV    849.7mV
6.901ns   806.9mV    685.6mV    943.8mV
8.249ns   862mV      750mV      990.5mV
16.16ns   916.5mV    817.6mV    1.037V
50ns      918.9mV    819.7mV    1.041V
[Rising Waveform]
R_fixture= 50.000
V_fixture= 1.800
V_fixture_min= 1.750
V_fixture_max= 1.850
|time   V(typ)   V(min)   V(max)
0s        880.5mV    923.9mV    812.4mV
449ps     879.9mV    924.1mV    831.5mV
479ps     878.3mV    924.2mV    910.5mV
555ps     920.7mV    922.4mV    1.224V
650ps     1.233V     952.7mV    1.461V
738ps     1.431V     1.184V     1.593V
870ps     1.604V     1.449V     1.718V
1.119ns   1.742V     1.659V     1.81V
1.57ns    1.792V     1.737V     1.844V
50ns      1.8V       1.75V      1.85V
[Falling Waveform]
R_fixture= 50.000
V_fixture= 1.800
V_fixture_min= 1.750
V_fixture_max= 1.850
|time   V(typ)   V(min)   V(max)
0s        1.8V       1.75V      1.85V
2.453ns   1.799V     1.747V     1.849V
3.172ns   1.772V     1.718V     1.811V
4.06ns    1.655V     1.618V     1.655V
5.262ns   1.384V     1.391V     1.345V
6.833ns   1.088V     1.125V     1.026V
7.703ns   989.9mV    1.036V     921.9mV
8.993ns   932.6mV    978.7mV    864.6mV
15.9ns    883.8mV    926.4mV    816.9mV
50ns      880.5mV    923.9mV    812.4mV
[Falling Waveform]
R_fixture= 50.000
V_fixture= 0.0
V_fixture_min= 0.0
V_fixture_max= 0.0
|time   V(typ)   V(min)   V(max)
0s        918.9mV    819.7mV    1.041V
492ps     919.7mV    819.7mV    1.02V
532ps     918.7mV    820mV      951.7mV
613ps     875.4mV    820.4mV    635.4mV
686ps     665.2mV    802.5mV    438.9mV
830ps     331.1mV    520.7mV    228.2mV
1.039ns   129.1mV    200.3mV    82.81mV
1.28ns    35.9mV     63.43mV    21.92mV
1.579ns   7.653mV    13.63mV    4.803mV
50ns      1.303uV    4.075uV    779.5nV
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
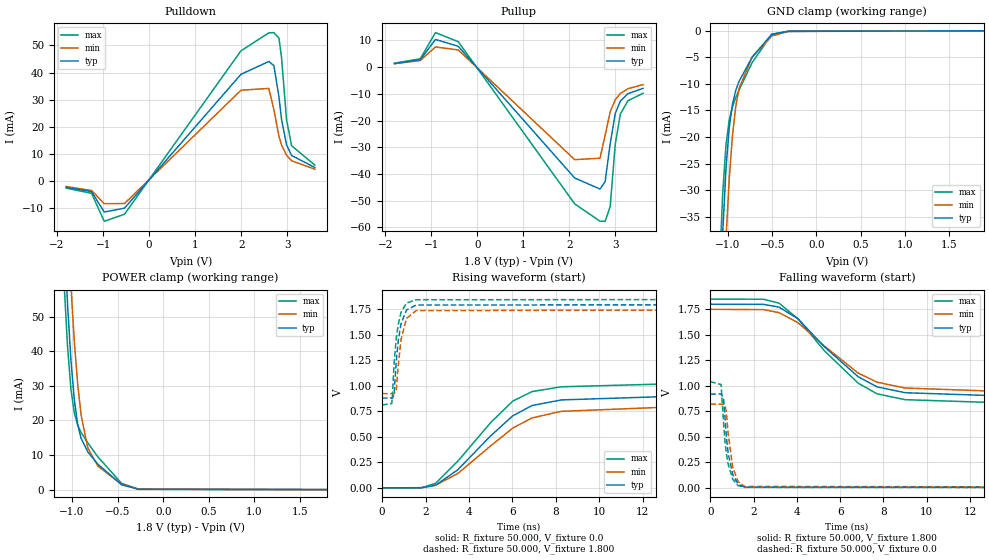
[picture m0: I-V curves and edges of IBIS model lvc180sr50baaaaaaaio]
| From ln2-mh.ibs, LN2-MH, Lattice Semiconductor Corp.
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|   Model lvc180sr50baaaaaaaio
[Model] lvc180sr50baaaaaaaio
Model_type I/O
Polarity   Non-Inverting
Enable   Active-Low
Vinl =  0.630V
Vinh =  1.170V
Vmeas =  0.900V
Cref =  0.0F
Rref =  1.000M
Vref =  0.0V
C_comp   2.000pF   1.500pF   2.500pF
[Temperature Range]   25.000   0.125k   -40.000
[Voltage Range]   1.800V   1.750V   1.850V
[C Comp Corner]
C_comp   2.000pF   1.500pF   2.500pF
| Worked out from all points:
|   slope of the pulldown table from 0 to 0.27 V, typ, clamps not added: 49.6 ohm
|   slope of the pullup table from 0 to 0.27 V, typ, clamps not added: 50.2 ohm
|   GND clamp passes 1 mA (typ) near -0.54 V on its own axis
|   POWER clamp passes 1 mA (typ) near -0.43 V on its own axis
|   rising waveform, R_fixture 50.000, V_fixture 0.0: 20-80 % time 2.69ns typ, 2.94ns min, 2.63ns max; typ from 0 V to 0.919 V
|   rising waveform, R_fixture 50.000, V_fixture 1.800: 20-80 % time 283ps typ, 290ps min, 279ps max; typ from 0.881 V to 1.8 V
|   falling waveform, R_fixture 50.000, V_fixture 1.800: 20-80 % time 2.75ns typ, 2.86ns min, 2.76ns max; typ from 1.8 V to 0.881 V
|   falling waveform, R_fixture 50.000, V_fixture 0.0: 20-80 % time 297ps typ, 306ps min, 288ps max; typ from 0.919 V to 0 V
[Pulldown]
|Voltage   I(typ)   I(min)   I(max)
-1.8V     -2.361mA   -2.135mA   -2.721mA
-1.25V    -4.029mA   -3.592mA   -4.634mA
-975mV    -11.55mA   -8.462mA   -14.97mA
-535mV    -10.11mA   -8.405mA   -12.35mA
1.995V    39.34mA    33.46mA    48.03mA
2.6V      44.08mA    34.13mA    54.65mA
2.71V     42.56mA    26.23mA    54.76mA
2.82V     31.04mA    16.49mA    52.69mA
2.875V    22.86mA    13.25mA    45.76mA
2.985V    13.31mA    9.425mA    22.57mA
3.095V    9.341mA    7.399mA    12.95mA
3.6V      4.905mA    4.286mA    5.788mA
[Pullup]
|Voltage   I(typ)   I(min)   I(max)
-1.8V     1.308mA    1.236mA    1.44mA
-1.24V    2.712mA    2.436mA    3.073mA
-910mV    10.32mA    7.509mA    12.89mA
-415mV    7.759mA    6.393mA    9.463mA
2.115V    -41.51mA   -34.65mA   -51.2mA
2.665V    -45.65mA   -34.09mA   -57.67mA
2.775V    -42.88mA   -25.59mA   -57.7mA
2.885V    -28.73mA   -16.79mA   -52.24mA
2.995V    -17.38mA   -12.23mA   -28.98mA
3.105V    -12.78mA   -9.912mA   -17.63mA
3.27V     -9.973mA   -8.118mA   -12.61mA
3.6V      -7.973mA   -6.561mA   -9.827mA
[GND_clamp]
|Voltage   I(typ)   I(min)   I(max)
-1.8V     -585.7mA   -591.6mA   -585.2mA
-1.097V   -54.7mA    -72.3mA    -45.45mA
-1.06V    -38.22mA   -54.4mA    -30.73mA
-1.023V   -26.05mA   -39.45mA   -21.57mA
-986mV    -18.23mA   -27.86mA   -16.82mA
-949mV    -13.77mA   -19.64mA   -14.3mA
-912mV    -11.21mA   -14.25mA   -12.59mA
-875mV    -9.522mA   -10.86mA   -11.14mA
-727mV    -4.965mA   -4.953mA   -5.98mA
-505mV    -637.4uA   -970.8uA   -651.9uA
-320mV    -95.22uA   -117.2uA   -94.14uA
1.89V     0A         0A         0A
[POWER_clamp]
|Voltage   I(typ)   I(min)   I(max)
-1.789V   650.9mA    666.7mA    643.9mA
-1.086V   73.39mA    99.36mA    59.11mA
-1.049V   53.39mA    77.76mA    41.22mA
-1.012V   37.33mA    58.73mA    28.98mA
-975mV    25.93mA    42.79mA    22.14mA
-938mV    18.88mA    30.44mA    18.64mA
-901mV    14.88mA    21.59mA    16.55mA
-827mV    10.9mA     12.03mA    13.51mA
-716mV    7.349mA    6.765mA    9.446mA
-457mV    1.407mA    1.575mA    1.826mA
-272mV    92.84uA    154.8uA    100.2uA
1.8V      0A         0A         0A
[Ramp]
| variable   typ   min   max
dV/dt_r   0.551/2.692n   0.492/2.947n   0.624/2.630n
dV/dt_f   0.552/2.755n   0.496/2.883n   0.623/2.776n
R_load = 50.000
[Rising Waveform]
R_fixture= 50.000
V_fixture= 0.0
V_fixture_min= 0.0
V_fixture_max= 0.0
|time   V(typ)   V(min)   V(max)
0s        367.3nV    3.507uV    105.1nV
1.813ns   596uV      1.292mV    1.429mV
2.461ns   25.79mV    25.9mV     44.73mV
3.483ns   176.9mV    139.9mV    260.8mV
4.991ns   508.4mV    410.5mV    637.8mV
6.013ns   705.9mV    585.6mV    850mV
6.901ns   806.9mV    685.6mV    943.8mV
8.249ns   862mV      750mV      990.5mV
16.16ns   916.5mV    817.6mV    1.037V
50ns      918.9mV    819.7mV    1.041V
[Rising Waveform]
R_fixture= 50.000
V_fixture= 1.800
V_fixture_min= 1.750
V_fixture_max= 1.850
|time   V(typ)   V(min)   V(max)
0s        880.5mV    923.9mV    812.4mV
444ps     880.3mV    924.1mV    826.3mV
474ps     878.3mV    924.2mV    891.2mV
555ps     920.6mV    922.4mV    1.224V
652ps     1.239V     955.3mV    1.464V
742ps     1.438V     1.194V     1.598V
873ps     1.607V     1.453V     1.72V
1.122ns   1.743V     1.66V      1.811V
1.573ns   1.792V     1.738V     1.844V
50ns      1.8V       1.75V      1.85V
[Falling Waveform]
R_fixture= 50.000
V_fixture= 1.800
V_fixture_min= 1.750
V_fixture_max= 1.850
|time   V(typ)   V(min)   V(max)
0s        1.8V       1.75V      1.85V
2.453ns   1.799V     1.747V     1.849V
3.171ns   1.772V     1.718V     1.811V
4.053ns   1.657V     1.619V     1.657V
5.263ns   1.384V     1.391V     1.345V
6.833ns   1.089V     1.125V     1.026V
7.703ns   990.2mV    1.036V     921.7mV
9.001ns   932.5mV    978.5mV    864.3mV
15.91ns   883.8mV    926.4mV    816.9mV
50ns      880.5mV    923.9mV    812.4mV
[Falling Waveform]
R_fixture= 50.000
V_fixture= 0.0
V_fixture_min= 0.0
V_fixture_max= 0.0
|time   V(typ)   V(min)   V(max)
0s        918.9mV    819.7mV    1.041V
500ps     920mV      819.7mV    1.013V
613ps     875.4mV    820.4mV    635.5mV
683ps     675mV      804.1mV    445.5mV
741ps     504.5mV    743.5mV    339.9mV
830ps     331.1mV    520.6mV    228.3mV
1.039ns   129.1mV    200.3mV    82.84mV
1.279ns   36.09mV    63.76mV    22.05mV
1.579ns   7.653mV    13.62mV    4.804mV
50ns      1.301uV    4.075uV    779.3nV
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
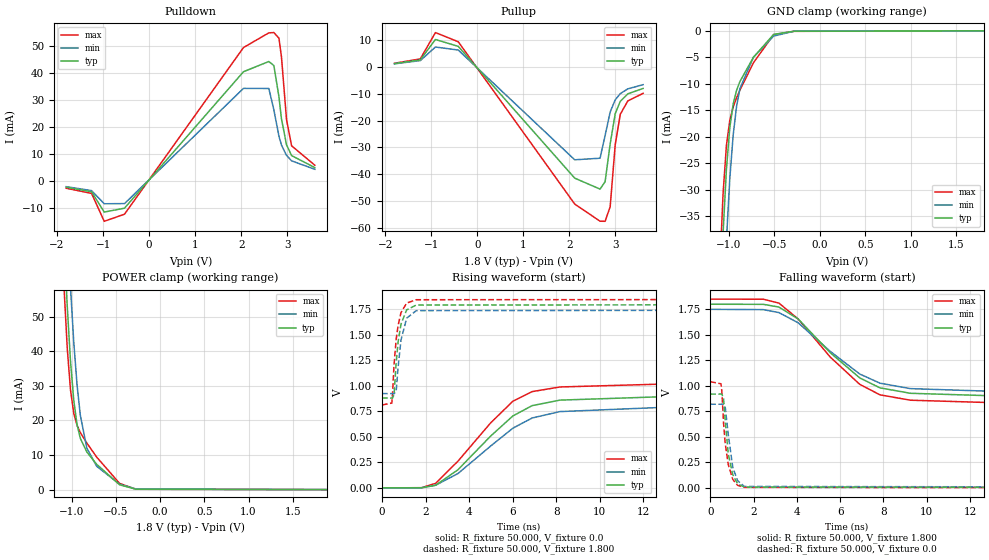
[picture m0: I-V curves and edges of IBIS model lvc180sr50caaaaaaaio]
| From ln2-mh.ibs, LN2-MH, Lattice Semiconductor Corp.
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|   Model lvc180sr50caaaaaaaio
[Model] lvc180sr50caaaaaaaio
Model_type I/O
Polarity   Non-Inverting
Enable   Active-Low
Vinl =  0.630V
Vinh =  1.170V
Vmeas =  0.900V
Cref =  0.0F
Rref =  1.000M
Vref =  0.0V
C_comp   2.000pF   1.500pF   2.500pF
[Temperature Range]   25.000   0.125k   -40.000
[Voltage Range]   1.800V   1.750V   1.850V
[C Comp Corner]
C_comp   2.000pF   1.500pF   2.500pF
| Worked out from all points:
|   slope of the pulldown table from 0 to 0.27 V, typ, clamps not added: 50.2 ohm
|   slope of the pullup table from 0 to 0.27 V, typ, clamps not added: 49.6 ohm
|   GND clamp passes 1 mA (typ) near -0.53 V on its own axis
|   POWER clamp passes 1 mA (typ) near -0.43 V on its own axis
|   rising waveform, R_fixture 50.000, V_fixture 0.0: 20-80 % time 2.69ns typ, 2.94ns min, 2.63ns max; typ from 0 V to 0.919 V
|   rising waveform, R_fixture 50.000, V_fixture 1.800: 20-80 % time 283ps typ, 290ps min, 279ps max; typ from 0.881 V to 1.8 V
|   falling waveform, R_fixture 50.000, V_fixture 1.800: 20-80 % time 2.75ns typ, 2.86ns min, 2.76ns max; typ from 1.8 V to 0.881 V
|   falling waveform, R_fixture 50.000, V_fixture 0.0: 20-80 % time 297ps typ, 306ps min, 288ps max; typ from 0.919 V to 0 V
[Pulldown]
|Voltage   I(typ)   I(min)   I(max)
-1.8V     -2.355mA   -2.13mA    -2.713mA
-1.25V    -4.018mA   -3.583mA   -4.621mA
-975mV    -11.52mA   -8.44mA    -14.92mA
-535mV    -10.07mA   -8.383mA   -12.3mA
2.05V     40.33mA    34.18mA    49.26mA
2.6V      44.1mA     34.15mA    54.68mA
2.71V     42.59mA    26.24mA    54.79mA
2.82V     31.06mA    16.5mA     52.72mA
2.875V    22.87mA    13.25mA    45.78mA
2.985V    13.32mA    9.429mA    22.58mA
3.095V    9.346mA    7.403mA    12.96mA
3.6V      4.908mA    4.289mA    5.792mA
[Pullup]
|Voltage   I(typ)   I(min)   I(max)
-1.8V     1.311mA    1.238mA    1.444mA
-1.24V    2.718mA    2.441mA    3.08mA
-910mV    10.34mA    7.524mA    12.93mA
-415mV    7.772mA    6.392mA    9.489mA
2.115V    -41.51mA   -34.65mA   -51.2mA
2.665V    -45.61mA   -34.06mA   -57.62mA
2.775V    -42.85mA   -25.57mA   -57.65mA
2.885V    -28.71mA   -16.77mA   -52.2mA
2.995V    -17.37mA   -12.22mA   -28.96mA
3.105V    -12.77mA   -9.905mA   -17.61mA
3.27V     -9.966mA   -8.112mA   -12.6mA
3.6V      -7.967mA   -6.556mA   -9.819mA
[GND_clamp]
|Voltage   I(typ)   I(min)   I(max)
-1.8V     -585.7mA   -591.6mA   -585.2mA
-1.097V   -54.72mA   -72.32mA   -45.47mA
-1.06V    -38.25mA   -54.42mA   -30.77mA
-1.023V   -26.08mA   -39.47mA   -21.61mA
-986mV    -18.26mA   -27.88mA   -16.87mA
-949mV    -13.8mA    -19.67mA   -14.35mA
-912mV    -11.24mA   -14.28mA   -12.64mA
-875mV    -9.559mA   -10.89mA   -11.19mA
-727mV    -5.003mA   -4.98mA    -6.032mA
-505mV    -676uA     -991.2uA   -711.7uA
-283mV    -81.53uA   -80.08uA   -96.55uA
1.8V      0A         0A         0A
[POWER_clamp]
|Voltage   I(typ)   I(min)   I(max)
-1.789V   650.9mA    666.7mA    643.9mA
-1.086V   73.38mA    99.35mA    59.1mA
-1.049V   53.37mA    77.75mA    41.2mA
-1.012V   37.32mA    58.72mA    28.95mA
-975mV    25.91mA    42.78mA    22.11mA
-938mV    18.86mA    30.43mA    18.61mA
-901mV    14.86mA    21.58mA    16.52mA
-827mV    10.88mA    12.01mA    13.47mA
-716mV    7.324mA    6.749mA    9.413mA
-457mV    1.39mA     1.571mA    1.797mA
-272mV    110.1uA    181.7uA    102.9uA
1.89V     0A         0A         0A
[Ramp]
| variable   typ   min   max
dV/dt_r   0.551/2.703n   0.492/2.940n   0.624/2.632n
dV/dt_f   0.552/2.764n   0.496/2.889n   0.623/2.757n
R_load = 50.000
[Rising Waveform]
R_fixture= 50.000
V_fixture= 0.0
V_fixture_min= 0.0
V_fixture_max= 0.0
|time   V(typ)   V(min)   V(max)
0s        367.3nV    3.507uV    105.1nV
1.815ns   602.3uV    1.315mV    1.458mV
2.46ns    25.7mV     25.84mV    44.61mV
3.485ns   177.3mV    140.2mV    261.3mV
4.989ns   507.9mV    410.1mV    637.3mV
6.009ns   705mV      585mV      849.4mV
6.895ns   806.3mV    685.1mV    943.5mV
8.169ns   860mV      747.6mV    988.9mV
16.16ns   916.5mV    817.6mV    1.037V
50ns      918.9mV    819.7mV    1.041V
[Rising Waveform]
R_fixture= 50.000
V_fixture= 1.800
V_fixture_min= 1.750
V_fixture_max= 1.850
|time   V(typ)   V(min)   V(max)
0s        880.5mV    923.9mV    812.4mV
449ps     879.9mV    924.1mV    831.5mV
479ps     878.3mV    924.2mV    910.5mV
552ps     915.3mV    922.5mV    1.214V
650ps     1.234V     952.6mV    1.461V
740ps     1.435V     1.189V     1.595V
870ps     1.605V     1.449V     1.718V
1.13ns    1.745V     1.663V     1.812V
1.57ns    1.792V     1.737V     1.844V
50ns      1.8V       1.75V      1.85V
[Falling Waveform]
R_fixture= 50.000
V_fixture= 1.800
V_fixture_min= 1.750
V_fixture_max= 1.850
|time   V(typ)   V(min)   V(max)
0s        1.8V       1.75V      1.85V
2.453ns   1.799V     1.747V     1.849V
3.171ns   1.772V     1.718V     1.811V
4.06ns    1.655V     1.618V     1.655V
5.541ns   1.325V     1.338V     1.282V
6.902ns   1.078V     1.116V     1.015V
7.839ns   980.2mV    1.026V     911.7mV
9.245ns   927mV      972.8mV    859.2mV
15.88ns   883.8mV    926.4mV    816.9mV
50ns      880.5mV    923.9mV    812.4mV
[Falling Waveform]
R_fixture= 50.000
V_fixture= 0.0
V_fixture_min= 0.0
V_fixture_max= 0.0
|time   V(typ)   V(min)   V(max)
0s        918.9mV    819.7mV    1.041V
492ps     919.7mV    819.7mV    1.02V
532ps     918.7mV    820mV      951.6mV
613ps     875.4mV    820.4mV    635.4mV
683ps     675mV      804.1mV    445.4mV
829ps     332.6mV    523.2mV    229.2mV
1.038ns   129.7mV    201.2mV    83.25mV
1.26ns    39.99mV    70.36mV    24.42mV
1.579ns   7.653mV    13.63mV    4.802mV
50ns      1.302uV    4.076uV    779.5nV
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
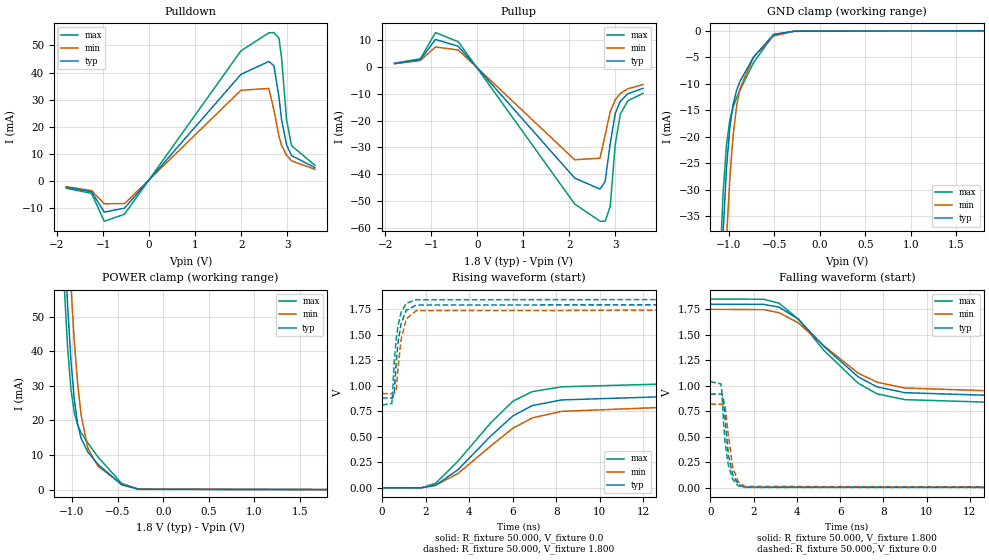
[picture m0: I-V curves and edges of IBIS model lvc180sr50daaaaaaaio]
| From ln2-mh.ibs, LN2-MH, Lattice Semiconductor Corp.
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|   Model lvc180sr50daaaaaaaio
[Model] lvc180sr50daaaaaaaio
Model_type I/O
Polarity   Non-Inverting
Enable   Active-Low
Vinl =  0.630V
Vinh =  1.170V
Vmeas =  0.900V
Cref =  0.0F
Rref =  1.000M
Vref =  0.0V
C_comp   2.000pF   1.500pF   2.500pF
[Temperature Range]   25.000   0.125k   -40.000
[Voltage Range]   1.800V   1.750V   1.850V
[C Comp Corner]
C_comp   2.000pF   1.500pF   2.500pF
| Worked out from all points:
|   slope of the pulldown table from 0 to 0.27 V, typ, clamps not added: 50.2 ohm
|   slope of the pullup table from 0 to 0.27 V, typ, clamps not added: 50.2 ohm
|   GND clamp passes 1 mA (typ) near -0.53 V on its own axis
|   POWER clamp passes 1 mA (typ) near -0.43 V on its own axis
|   rising waveform, R_fixture 50.000, V_fixture 0.0: 20-80 % time 2.69ns typ, 2.94ns min, 2.63ns max; typ from 0 V to 0.919 V
|   rising waveform, R_fixture 50.000, V_fixture 1.800: 20-80 % time 283ps typ, 290ps min, 279ps max; typ from 0.881 V to 1.8 V
|   falling waveform, R_fixture 50.000, V_fixture 1.800: 20-80 % time 2.75ns typ, 2.86ns min, 2.76ns max; typ from 1.8 V to 0.881 V
|   falling waveform, R_fixture 50.000, V_fixture 0.0: 20-80 % time 297ps typ, 306ps min, 288ps max; typ from 0.919 V to 0 V
[Pulldown]
|Voltage   I(typ)   I(min)   I(max)
-1.8V     -2.355mA   -2.13mA    -2.713mA
-1.25V    -4.018mA   -3.583mA   -4.621mA
-975mV    -11.52mA   -8.44mA    -14.92mA
-535mV    -10.07mA   -8.383mA   -12.3mA
1.995V    39.34mA    33.46mA    48.03mA
2.6V      44.08mA    34.13mA    54.65mA
2.71V     42.56mA    26.23mA    54.76mA
2.82V     31.04mA    16.49mA    52.69mA
2.875V    22.86mA    13.25mA    45.76mA
2.985V    13.31mA    9.425mA    22.57mA
3.095V    9.341mA    7.399mA    12.95mA
3.6V      4.905mA    4.286mA    5.788mA
[Pullup]
|Voltage   I(typ)   I(min)   I(max)
-1.8V     1.308mA    1.236mA    1.44mA
-1.24V    2.712mA    2.436mA    3.073mA
-910mV    10.32mA    7.509mA    12.89mA
-415mV    7.759mA    6.393mA    9.463mA
2.115V    -41.51mA   -34.65mA   -51.2mA
2.665V    -45.61mA   -34.06mA   -57.62mA
2.775V    -42.85mA   -25.57mA   -57.65mA
2.885V    -28.71mA   -16.77mA   -52.2mA
2.995V    -17.37mA   -12.22mA   -28.96mA
3.105V    -12.77mA   -9.905mA   -17.61mA
3.27V     -9.966mA   -8.112mA   -12.6mA
3.6V      -7.967mA   -6.556mA   -9.819mA
[GND_clamp]
|Voltage   I(typ)   I(min)   I(max)
-1.8V     -585.7mA   -591.6mA   -585.2mA
-1.097V   -54.72mA   -72.32mA   -45.47mA
-1.06V    -38.25mA   -54.42mA   -30.77mA
-1.023V   -26.08mA   -39.47mA   -21.61mA
-986mV    -18.26mA   -27.88mA   -16.87mA
-949mV    -13.8mA    -19.67mA   -14.35mA
-912mV    -11.24mA   -14.28mA   -12.64mA
-875mV    -9.559mA   -10.89mA   -11.19mA
-727mV    -5.003mA   -4.98mA    -6.032mA
-505mV    -676uA     -991.2uA   -711.7uA
-283mV    -81.53uA   -80.08uA   -96.55uA
1.8V      -11.32nA   0A         -15.28uA
[POWER_clamp]
|Voltage   I(typ)   I(min)   I(max)
-1.789V   650.9mA    666.7mA    643.9mA
-1.086V   73.39mA    99.36mA    59.11mA
-1.049V   53.39mA    77.76mA    41.22mA
-1.012V   37.33mA    58.73mA    28.98mA
-975mV    25.93mA    42.79mA    22.14mA
-938mV    18.88mA    30.44mA    18.64mA
-901mV    14.88mA    21.59mA    16.55mA
-827mV    10.9mA     12.03mA    13.51mA
-716mV    7.349mA    6.765mA    9.446mA
-457mV    1.407mA    1.575mA    1.826mA
-272mV    92.84uA    154.8uA    100.2uA
1.8V      0A         0A         15.76uA
[Ramp]
| variable   typ   min   max
dV/dt_r   0.551/2.689n   0.492/2.943n   0.624/2.631n
dV/dt_f   0.552/2.748n   0.496/2.866n   0.623/2.756n
R_load = 50.000
[Rising Waveform]
R_fixture= 50.000
V_fixture= 0.0
V_fixture_min= 0.0
V_fixture_max= 0.0
|time   V(typ)   V(min)   V(max)
0s        367.3nV    3.507uV    105.1nV
1.815ns   602.3uV    1.314mV    1.463mV
2.464ns   26.01mV    26.1mV     45.14mV
3.485ns   177.3mV    140.2mV    261.3mV
4.99ns    508.1mV    410.3mV    637.4mV
6.011ns   705.3mV    585.3mV    849.4mV
6.896ns   806.3mV    685.2mV    943.4mV
8.245ns   861.8mV    749.8mV    990.3mV
16.27ns   916.6mV    817.7mV    1.038V
50ns      918.9mV    819.7mV    1.041V
[Rising Waveform]
R_fixture= 50.000
V_fixture= 1.800
V_fixture_min= 1.750
V_fixture_max= 1.850
|time   V(typ)   V(min)   V(max)
0s        880.5mV    923.9mV    812.4mV
444ps     880.3mV    924.1mV    826.2mV
474ps     878.3mV    924.2mV    890.8mV
555ps     920.7mV    922.4mV    1.224V
650ps     1.234V     952.7mV    1.461V
739ps     1.433V     1.186V     1.594V
870ps     1.604V     1.449V     1.718V
1.113ns   1.741V     1.656V     1.809V
1.57ns    1.792V     1.737V     1.844V
50ns      1.8V       1.75V      1.85V
[Falling Waveform]
R_fixture= 50.000
V_fixture= 1.800
V_fixture_min= 1.750
V_fixture_max= 1.850
|time   V(typ)   V(min)   V(max)
0s        1.8V       1.75V      1.85V
2.453ns   1.799V     1.747V     1.849V
3.172ns   1.772V     1.718V     1.811V
4.062ns   1.655V     1.618V     1.655V
5.262ns   1.384V     1.391V     1.345V
6.832ns   1.089V     1.125V     1.026V
7.702ns   990.3mV    1.036V     922mV
8.992ns   932.7mV    978.7mV    864.6mV
16.56ns   882.6mV    925.5mV    815.7mV
50ns      880.5mV    923.9mV    812.4mV
[Falling Waveform]
R_fixture= 50.000
V_fixture= 0.0
V_fixture_min= 0.0
V_fixture_max= 0.0
|time   V(typ)   V(min)   V(max)
0s        918.9mV    819.7mV    1.041V
492ps     919.7mV    819.7mV    1.02V
532ps     918.7mV    820mV      951.7mV
613ps     875.4mV    820.4mV    635.4mV
686ps     665.2mV    802.5mV    438.9mV
830ps     331.1mV    520.7mV    228.2mV
1.039ns   129.1mV    200.3mV    82.81mV
1.28ns    35.9mV     63.43mV    21.92mV
1.58ns    7.616mV    13.56mV    4.78mV
50ns      1.302uV    4.076uV    779.6nV
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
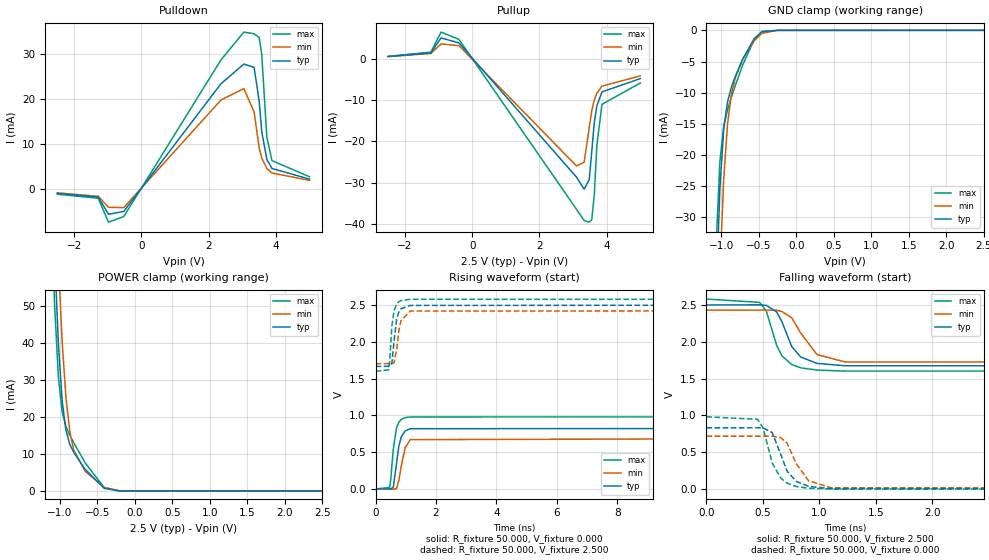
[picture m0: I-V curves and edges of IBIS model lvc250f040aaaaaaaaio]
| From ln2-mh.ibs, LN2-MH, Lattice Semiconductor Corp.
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|   Model lvc250f040aaaaaaaaio
[Model] lvc250f040aaaaaaaaio
Model_type I/O
Polarity   Non-Inverting
Enable   Active-Low
Vinl =  0.700V
Vinh =  1.700V
Vmeas =  1.250V
Cref =  0.0F
Rref =  1.000M
Vref =  0.0V
C_comp   2.000pF   1.500pF   2.500pF
[Temperature Range]   25.000   0.125k   -40.000
[Voltage Range]   2.500V   2.430V   2.580V
[C Comp Corner]
C_comp   2.000pF   1.500pF   2.500pF
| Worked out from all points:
|   slope of the pulldown table from 0 to 0.375 V, typ, clamps not added: 98.4 ohm
|   slope of the pullup table from 0 to 0.375 V, typ, clamps not added: 98.8 ohm
|   GND clamp passes 1 mA (typ) near -0.54 V on its own axis
|   POWER clamp passes 1 mA (typ) near -0.43 V on its own axis
|   rising waveform, R_fixture 50.000, V_fixture 0.000: 20-80 % time 173ps typ, 211ps min, 149ps max; typ from 0 V to 0.832 V
|   rising waveform, R_fixture 50.000, V_fixture 2.500: 20-80 % time 133ps typ, 156ps min, 116ps max; typ from 1.67 V to 2.5 V
|   falling waveform, R_fixture 50.000, V_fixture 2.500: 20-80 % time 154ps typ, 183ps min, 137ps max; typ from 2.5 V to 1.67 V
|   falling waveform, R_fixture 50.000, V_fixture 0.000: 20-80 % time 131ps typ, 146ps min, 122ps max; typ from 0.832 V to 0 V
[Pulldown]
|Voltage   I(typ)   I(min)   I(max)
-2.5V     -1.032mA   -909.3uA   -1.218mA
-1.284V   -1.851mA   -1.671mA   -2.11mA
-980mV    -5.675mA   -4.136mA   -7.436mA
-524mV    -5.036mA   -4.185mA   -6.17mA
2.364V    23.34mA    19.74mA    28.65mA
3.048V    27.76mA    22.28mA    34.86mA
3.352V    27mA       17.12mA    34.49mA
3.504V    19.49mA    9.078mA    33.65mA
3.58V     12.69mA    6.807mA    29.84mA
3.732V    6.511mA    4.539mA    11.47mA
3.884V    4.51mA     3.504mA    6.259mA
5V        2.148mA    1.868mA    2.677mA
[Pullup]
|Voltage   I(typ)   I(min)   I(max)
-2.5V     516.3uA    476uA      541.2uA
-1.232V   1.373mA    1.231mA    1.559mA
-928mV    5.006mA    3.543mA    6.413mA
-396mV    3.796mA    3.125mA    4.64mA
3.1V      -28.68mA   -25.97mA   -36.47mA
3.328V    -31.61mA   -25.1mA    -39.18mA
3.48V     -29.32mA   -16.75mA   -39.6mA
3.556V    -22.47mA   -12.59mA   -38.99mA
3.632V    -15.36mA   -9.98mA    -32.87mA
3.708V    -11.44mA   -8.392mA   -20.9mA
3.86V     -8.058mA   -6.662mA   -11.07mA
5V        -4.848mA   -4.198mA   -5.912mA
[GND_clamp]
|Voltage   I(typ)   I(min)   I(max)
-2.5V     -1.176A    -1.175A    -1.18A
-1.072V   -43.12mA   -59.87mA   -34.84mA
-1.021V   -25.46mA   -38.72mA   -21.1mA
-970mV    -15.9mA    -23.88mA   -15.42mA
-919mV    -11.5mA    -15.05mA   -12.74mA
-868mV    -9.155mA   -10.31mA   -10.74mA
-817mV    -7.451mA   -7.678mA   -8.924mA
-715mV    -4.588mA   -4.605mA   -5.525mA
-562mV    -1.31mA    -1.648mA   -1.483mA
-460mV    -221.2uA   -492.9uA   -183.3uA
-256mV    -336.9nA   -5.429uA   -53.89nA
2.5V      0A         0A         0A
[POWER_clamp]
|Voltage   I(typ)   I(min)   I(max)
-2.498V   1.294A     1.303A     1.292A
-1.121V   95.13mA    121.6mA    80.05mA
-1.07V    64.31mA    89.69mA    50.73mA
-1.019V   40mA       62.1mA     30.81mA
-968mV    24.27mA    40.19mA    21.27mA
-917mV    16.31mA    24.99mA    17.34mA
-866mV    12.6mA     15.97mA    15.03mA
-815mV    10.45mA    11.12mA    13.06mA
-662mV    5.856mA    5.328mA    7.611mA
-407mV    698.4uA    949.4uA    879.7uA
-203mV    1.851uA    18.03uA    575.7nA
2.5V      0A         0A         0A
[Ramp]
| variable   typ   min   max
dV/dt_r   0.510/0.174n   0.441/0.212n   0.602/0.150n
dV/dt_f   0.511/0.155n   0.446/0.185n   0.601/0.137n
R_load = 50.000
[Rising Waveform]
R_fixture = 50.000
V_fixture = 0.000
V_fixture_min = 0.000
V_fixture_max = 0.000
|  time   V(typ)   V(min)   V(max)
0s        2.224uV    10.27uV    1.34uV
464ps     -1.289mV   -253.7uV   19.93mV
503ps     -3.031mV   -147.6uV   133.4mV
587ps     26.56mV    -2.302mV   542.5mV
691ps     340.3mV    4.116mV    827.3mV
770ps     583.9mV    115.6mV    907.5mV
849ps     706.9mV    311.1mV    945mV
979ps     787.8mV    559mV      969.2mV
1.149ns   818.4mV    670.1mV    977.8mV
50ns      832.5mV    719mV      983.1mV
[Rising Waveform]
R_fixture = 50.000
V_fixture = 2.500
V_fixture_min = 2.430
V_fixture_max = 2.580
|  time   V(typ)   V(min)   V(max)
0s        1.665V     1.702V     1.599V
429ps     1.666V     1.703V     1.618V
465ps     1.665V     1.703V     1.733V
539ps     1.709V     1.703V     2.215V
611ps     2.005V     1.714V     2.422V
701ps     2.318V     1.913V     2.516V
778ps     2.413V     2.171V     2.547V
838ps     2.448V     2.286V     2.559V
1.148ns   2.494V     2.417V     2.577V
50ns      2.5V       2.43V      2.58V
[Falling Waveform]
R_fixture = 50.000
V_fixture = 2.500
V_fixture_min = 2.430
V_fixture_max = 2.580
|  time   V(typ)   V(min)   V(max)
0s        2.5V       2.43V      2.58V
471ps     2.501V     2.43V      2.535V
531ps     2.494V     2.43V      2.414V
622ps     2.405V     2.428V     1.951V
668ps     2.274V     2.411V     1.81V
755ps     1.936V     2.326V     1.691V
834ps     1.795V     2.12V      1.647V
978ps     1.707V     1.828V     1.616V
1.228ns   1.675V     1.726V     1.603V
50ns      1.665V     1.702V     1.599V
[Falling Waveform]
R_fixture = 50.000
V_fixture = 0.000
V_fixture_min = 0.000
V_fixture_max = 0.000
|  time   V(typ)   V(min)   V(max)
0s        832.5mV    719mV      983.1mV
453ps     832.8mV    718.8mV    948mV
501ps     831mV      718.8mV    833.3mV
582ps     768.9mV    719mV      357.9mV
657ps     476.6mV    698.3mV    151mV
714ps     245.1mV    626.1mV    82.75mV
795ps     106.3mV    346.9mV    36.38mV
904ps     37.48mV    114.4mV    12.54mV
1.103ns   6.083mV    19.12mV    2mV
50ns      2.224uV    10.27uV    1.34uV
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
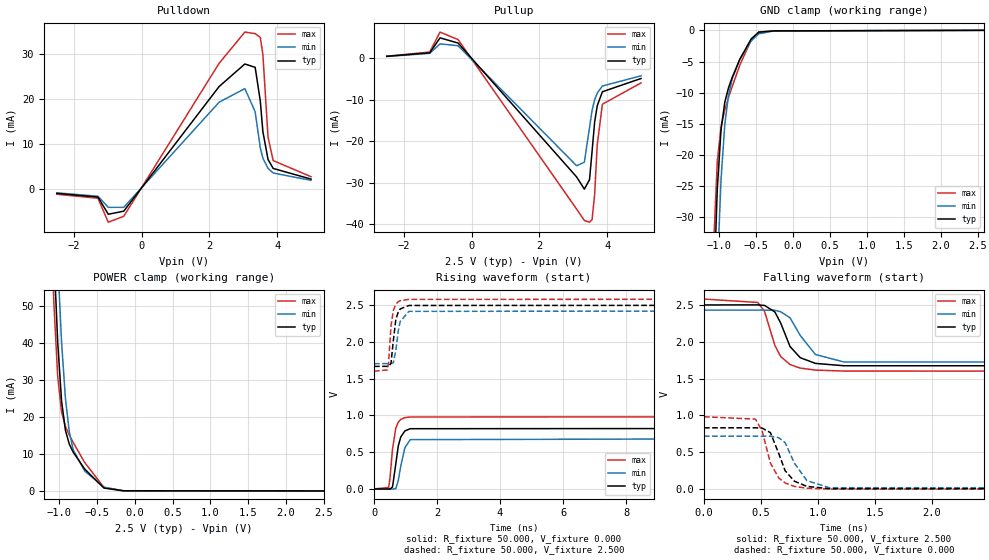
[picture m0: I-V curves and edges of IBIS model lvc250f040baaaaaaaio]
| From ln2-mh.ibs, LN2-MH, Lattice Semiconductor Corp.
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|   Model lvc250f040baaaaaaaio
[Model] lvc250f040baaaaaaaio
Model_type I/O
Polarity   Non-Inverting
Enable   Active-Low
Vinl =  0.700V
Vinh =  1.700V
Vmeas =  1.250V
Cref =  0.0F
Rref =  1.000M
Vref =  0.0V
C_comp   2.000pF   1.500pF   2.500pF
[Temperature Range]   25.000   0.125k   -40.000
[Voltage Range]   2.500V   2.430V   2.580V
[C Comp Corner]
C_comp   2.000pF   1.500pF   2.500pF
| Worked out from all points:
|   slope of the pulldown table from 0 to 0.375 V, typ, clamps not added: 98.4 ohm
|   slope of the pullup table from 0 to 0.375 V, typ, clamps not added: 101 ohm
|   GND clamp passes 1 mA (typ) near -0.53 V on its own axis
|   POWER clamp passes 1 mA (typ) near -0.42 V on its own axis
|   rising waveform, R_fixture 50.000, V_fixture 0.000: 20-80 % time 173ps typ, 211ps min, 149ps max; typ from 0 V to 0.832 V
|   rising waveform, R_fixture 50.000, V_fixture 2.500: 20-80 % time 133ps typ, 156ps min, 116ps max; typ from 1.67 V to 2.5 V
|   falling waveform, R_fixture 50.000, V_fixture 2.500: 20-80 % time 154ps typ, 183ps min, 137ps max; typ from 2.5 V to 1.67 V
|   falling waveform, R_fixture 50.000, V_fixture 0.000: 20-80 % time 131ps typ, 145ps min, 122ps max; typ from 0.832 V to 0 V
[Pulldown]
|Voltage   I(typ)   I(min)   I(max)
-2.5V     -1.031mA   -907.8uA   -1.217mA
-1.284V   -1.848mA   -1.668mA   -2.108mA
-980mV    -5.663mA   -4.124mA   -7.425mA
-524mV    -4.98mA    -4.135mA   -6.114mA
2.288V    22.69mA    19.21mA    27.85mA
3.048V    27.71mA    22.24mA    34.79mA
3.352V    26.96mA    17.1mA     34.45mA
3.504V    19.46mA    9.065mA    33.61mA
3.58V     12.67mA    6.797mA    29.81mA
3.732V    6.503mA    4.532mA    11.46mA
3.884V    4.504mA    3.498mA    6.252mA
5V        2.145mA    1.865mA    2.674mA
[Pullup]
|Voltage   I(typ)   I(min)   I(max)
-2.5V     513.3uA    473.2uA    538uA
-1.232V   1.365mA    1.223mA    1.55mA
-928mV    4.971mA    3.518mA    6.37mA
-396mV    3.724mA    3.071mA    4.557mA
3.1V      -28.64mA   -25.94mA   -36.42mA
3.328V    -31.59mA   -25.08mA   -39.16mA
3.48V     -29.31mA   -16.74mA   -39.58mA
3.556V    -22.46mA   -12.59mA   -38.98mA
3.632V    -15.36mA   -9.976mA   -32.86mA
3.708V    -11.44mA   -8.388mA   -20.89mA
3.86V     -8.055mA   -6.66mA    -11.07mA
5V        -4.847mA   -4.197mA   -5.91mA
[GND_clamp]
|Voltage   I(typ)   I(min)   I(max)
-2.5V     -1.176A    -1.175A    -1.18A
-1.072V   -43.12mA   -59.88mA   -34.84mA
-1.021V   -25.47mA   -38.73mA   -21.11mA
-970mV    -15.91mA   -23.89mA   -15.44mA
-919mV    -11.52mA   -15.06mA   -12.75mA
-868mV    -9.172mA   -10.33mA   -10.76mA
-817mV    -7.47mA    -7.698mA   -8.941mA
-715mV    -4.614mA   -4.632mA   -5.549mA
-562mV    -1.356mA   -1.692mA   -1.528mA
-460mV    -296.7uA   -557.9uA   -261.8uA
-256mV    -93.15uA   -97.62uA   -93.76uA
2.58V     0A         0A         0A
[POWER_clamp]
|Voltage   I(typ)   I(min)   I(max)
-2.498V   1.294A     1.303A     1.292A
-1.121V   95.14mA    121.6mA    80.07mA
-1.07V    64.33mA    89.71mA    50.75mA
-1.019V   40.02mA    62.12mA    30.84mA
-968mV    24.3mA     40.21mA    21.31mA
-917mV    16.34mA    25.01mA    17.39mA
-866mV    12.64mA    16mA       15.07mA
-815mV    10.49mA    11.15mA    13.11mA
-662mV    5.902mA    5.367mA    7.663mA
-407mV    768.2uA    1.002mA    960.5uA
-152mV    40.9uA     39.04uA    48.9uA
2.5V      0A         0A         0A
[Ramp]
| variable   typ   min   max
dV/dt_r   0.510/0.174n   0.441/0.212n   0.602/0.150n
dV/dt_f   0.511/0.155n   0.446/0.185n   0.601/0.137n
R_load = 50.000
[Rising Waveform]
R_fixture = 50.000
V_fixture = 0.000
V_fixture_min = 0.000
V_fixture_max = 0.000
|  time   V(typ)   V(min)   V(max)
0s        1.26uV     11.11uV    2.733uV
464ps     -1.285mV   -252.9uV   19.93mV
503ps     -3.029mV   -147uV     133.4mV
587ps     26.56mV    -2.295mV   542.5mV
692ps     344mV      4.585mV    828.7mV
769ps     581.7mV    113.3mV    906.9mV
849ps     706.9mV    310.9mV    945mV
979ps     787.8mV    558.9mV    969.2mV
1.149ns   818.4mV    670mV      977.8mV
50ns      832.5mV    719mV      983.1mV
[Rising Waveform]
R_fixture = 50.000
V_fixture = 2.500
V_fixture_min = 2.430
V_fixture_max = 2.580
|  time   V(typ)   V(min)   V(max)
0s        1.665V     1.702V     1.599V
429ps     1.666V     1.703V     1.618V
465ps     1.665V     1.703V     1.733V
539ps     1.709V     1.703V     2.215V
612ps     2.011V     1.714V     2.424V
692ps     2.301V     1.882V     2.51V
770ps     2.407V     2.149V     2.545V
832ps     2.446V     2.277V     2.558V
1.11ns    2.493V     2.413V     2.576V
50ns      2.5V       2.43V      2.58V
[Falling Waveform]
R_fixture = 50.000
V_fixture = 2.500
V_fixture_min = 2.430
V_fixture_max = 2.580
|  time   V(typ)   V(min)   V(max)
0s        2.5V       2.43V      2.58V
472ps     2.501V     2.43V      2.534V
532ps     2.493V     2.43V      2.41V
622ps     2.405V     2.428V     1.951V
673ps     2.255V     2.408V     1.8V
755ps     1.936V     2.326V     1.691V
845ps     1.784V     2.086V     1.643V
978ps     1.707V     1.828V     1.616V
1.228ns   1.675V     1.726V     1.603V
50ns      1.665V     1.702V     1.599V
[Falling Waveform]
R_fixture = 50.000
V_fixture = 0.000
V_fixture_min = 0.000
V_fixture_max = 0.000
|  time   V(typ)   V(min)   V(max)
0s        832.5mV    719mV      983.1mV
451ps     832.8mV    718.8mV    950.5mV
509ps     829.5mV    718.9mV    796.9mV
583ps     767.2mV    719mV      353.2mV
655ps     487.8mV    699.7mV    154.3mV
712ps     250.7mV    630.4mV    84.58mV
793ps     108.4mV    354.4mV    37.15mV
903ps     37.83mV    115.5mV    12.67mV
1.103ns   6.085mV    19.13mV    2.003mV
50ns      1.26uV     11.11uV    2.733uV
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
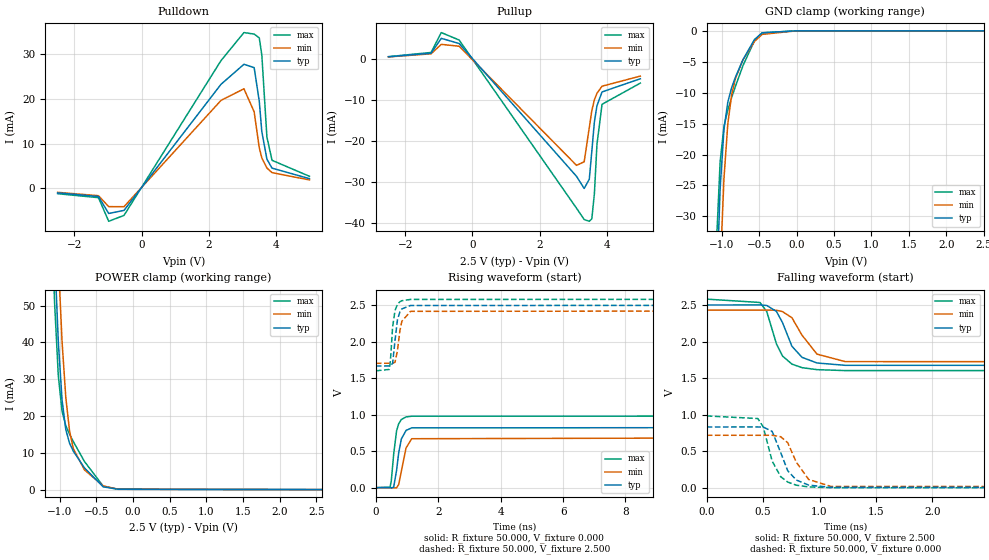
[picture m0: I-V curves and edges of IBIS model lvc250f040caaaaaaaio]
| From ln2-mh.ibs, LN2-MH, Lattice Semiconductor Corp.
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|   Model lvc250f040caaaaaaaio
[Model] lvc250f040caaaaaaaio
Model_type I/O
Polarity   Non-Inverting
Enable   Active-Low
Vinl =  0.700V
Vinh =  1.700V
Vmeas =  1.250V
Cref =  0.0F
Rref =  1.000M
Vref =  0.0V
C_comp   2.000pF   1.500pF   2.500pF
[Temperature Range]   25.000   0.125k   -40.000
[Voltage Range]   2.500V   2.430V   2.580V
[C Comp Corner]
C_comp   2.000pF   1.500pF   2.500pF
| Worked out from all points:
|   slope of the pulldown table from 0 to 0.375 V, typ, clamps not added: 101 ohm
|   slope of the pullup table from 0 to 0.375 V, typ, clamps not added: 98.8 ohm
|   GND clamp passes 1 mA (typ) near -0.53 V on its own axis
|   POWER clamp passes 1 mA (typ) near -0.43 V on its own axis
|   rising waveform, R_fixture 50.000, V_fixture 0.000: 20-80 % time 173ps typ, 211ps min, 149ps max; typ from 0 V to 0.832 V
|   rising waveform, R_fixture 50.000, V_fixture 2.500: 20-80 % time 133ps typ, 156ps min, 116ps max; typ from 1.67 V to 2.5 V
|   falling waveform, R_fixture 50.000, V_fixture 2.500: 20-80 % time 154ps typ, 183ps min, 137ps max; typ from 2.5 V to 1.67 V
|   falling waveform, R_fixture 50.000, V_fixture 0.000: 20-80 % time 131ps typ, 146ps min, 122ps max; typ from 0.832 V to 0 V
[Pulldown]
|Voltage   I(typ)   I(min)   I(max)
-2.5V     -1.026mA   -903.5uA   -1.21mA
-1.284V   -1.838mA   -1.659mA   -2.096mA
-980mV    -5.631mA   -4.103mA   -7.38mA
-524mV    -4.941mA   -4.114mA   -6.055mA
2.364V    23.25mA    19.65mA    28.55mA
3.048V    27.73mA    22.25mA    34.82mA
3.352V    26.98mA    17.11mA    34.48mA
3.504V    19.48mA    9.073mA    33.64mA
3.58V     12.68mA    6.803mA    29.83mA
3.732V    6.508mA    4.536mA    11.47mA
3.884V    4.508mA    3.502mA    6.258mA
5V        2.148mA    1.867mA    2.677mA
[Pullup]
|Voltage   I(typ)   I(min)   I(max)
-2.5V     515.5uA    475uA      540.5uA
-1.232V   1.371mA    1.228mA    1.557mA
-928mV    4.994mA    3.531mA    6.402mA
-396mV    3.735mA    3.069mA    4.582mA
3.1V      -28.6mA    -25.92mA   -36.36mA
3.328V    -31.55mA   -25.06mA   -39.11mA
3.48V     -29.28mA   -16.73mA   -39.54mA
3.556V    -22.44mA   -12.58mA   -38.93mA
3.632V    -15.34mA   -9.966mA   -32.82mA
3.708V    -11.42mA   -8.38mA    -20.87mA
3.86V     -8.047mA   -6.653mA   -11.06mA
5V        -4.842mA   -4.193mA   -5.904mA
[GND_clamp]
|Voltage   I(typ)   I(min)   I(max)
-2.5V     -1.176A    -1.175A    -1.18A
-1.072V   -43.15mA   -59.89mA   -34.87mA
-1.021V   -25.5mA    -38.75mA   -21.15mA
-970mV    -15.94mA   -23.91mA   -15.48mA
-919mV    -11.55mA   -15.09mA   -12.8mA
-868mV    -9.208mA   -10.36mA   -10.81mA
-817mV    -7.507mA   -7.725mA   -8.99mA
-715mV    -4.652mA   -4.658mA   -5.6mA
-562mV    -1.396mA   -1.715mA   -1.585mA
-460mV    -331.3uA   -573.9uA   -320.1uA
-1mV      -317.6nA   -575.7nA   -335.3nA
2.5V      0A         0A         0A
[POWER_clamp]
|Voltage   I(typ)   I(min)   I(max)
-2.498V   1.294A     1.303A     1.292A
-1.121V   95.13mA    121.6mA    80.05mA
-1.07V    64.32mA    89.7mA     50.73mA
-1.019V   40.01mA    62.11mA    30.82mA
-968mV    24.28mA    40.2mA     21.28mA
-917mV    16.32mA    25mA       17.36mA
-866mV    12.61mA    15.98mA    15.04mA
-815mV    10.46mA    11.14mA    13.07mA
-662mV    5.878mA    5.353mA    7.63mA
-407mV    756.4uA    1.004mA    934.2uA
-203mV    93.32uA    107.9uA    92.71uA
2.58V     0A         0A         0A
[Ramp]
| variable   typ   min   max
dV/dt_r   0.510/0.174n   0.441/0.212n   0.602/0.149n
dV/dt_f   0.511/0.155n   0.446/0.185n   0.601/0.137n
R_load = 50.000
[Rising Waveform]
R_fixture = 50.000
V_fixture = 0.000
V_fixture_min = 0.000
V_fixture_max = 0.000
|  time   V(typ)   V(min)   V(max)
0s        9.948uV    -75.96uV   -34.58uV
454ps     -828.2uV   -355uV     8.358mV
494ps     -2.668mV   -261.5uV   98.35mV
568ps     5.749mV    -1.677mV   451.3mV
662ps     234mV      -2.675mV   777.4mV
730ps     476.1mV    41.83mV    874.6mV
817ps     667.8mV    228.8mV    933.1mV
968ps     783.9mV    545.3mV    968.1mV
1.148ns   818.3mV    669.7mV    977.7mV
50ns      832.5mV    719mV      983.1mV
[Rising Waveform]
R_fixture = 50.000
V_fixture = 2.500
V_fixture_min = 2.430
V_fixture_max = 2.580
|  time   V(typ)   V(min)   V(max)
0s        1.665V     1.702V     1.599V
429ps     1.666V     1.703V     1.618V
465ps     1.665V     1.703V     1.733V
536ps     1.703V     1.703V     2.201V
613ps     2.016V     1.715V     2.425V
692ps     2.301V     1.882V     2.51V
770ps     2.407V     2.149V     2.545V
832ps     2.446V     2.277V     2.558V
1.11ns    2.493V     2.413V     2.576V
50ns      2.5V       2.43V      2.58V
[Falling Waveform]
R_fixture = 50.000
V_fixture = 2.500
V_fixture_min = 2.430
V_fixture_max = 2.580
|  time   V(typ)   V(min)   V(max)
0s        2.5V       2.43V      2.58V
472ps     2.501V     2.43V      2.534V
532ps     2.493V     2.43V      2.41V
618ps     2.412V     2.428V     1.968V
672ps     2.259V     2.409V     1.802V
755ps     1.936V     2.326V     1.692V
845ps     1.784V     2.086V     1.643V
978ps     1.707V     1.828V     1.616V
1.228ns   1.675V     1.726V     1.603V
50ns      1.665V     1.702V     1.599V
[Falling Waveform]
R_fixture = 50.000
V_fixture = 0.000
V_fixture_min = 0.000
V_fixture_max = 0.000
|  time   V(typ)   V(min)   V(max)
0s        832.5mV    719mV      983.1mV
453ps     832.9mV    718.8mV    947.7mV
501ps     830.9mV    718.8mV    832.5mV
580ps     771.9mV    719.2mV    365.9mV
656ps     481.3mV    699mV      152.2mV
718ps     233.9mV    617.7mV    79.3mV
794ps     107.2mV    350.6mV    36.63mV
904ps     37.45mV    114.3mV    12.48mV
1.103ns   6.088mV    19.04mV    1.961mV
50ns      9.948uV    -75.96uV   -34.58uV
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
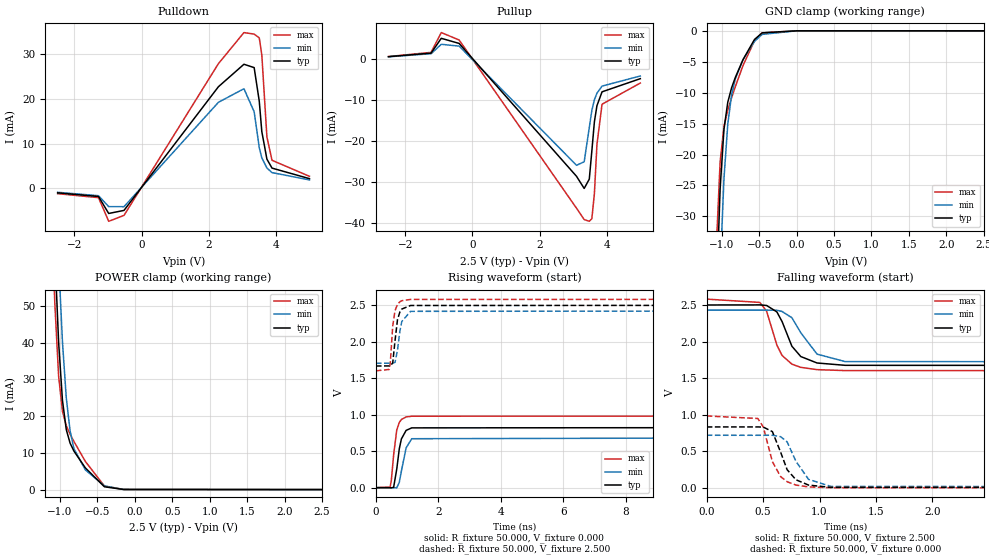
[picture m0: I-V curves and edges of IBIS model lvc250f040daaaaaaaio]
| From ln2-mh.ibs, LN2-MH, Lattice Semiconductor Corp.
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|   Model lvc250f040daaaaaaaio
[Model] lvc250f040daaaaaaaio
Model_type I/O
Polarity   Non-Inverting
Enable   Active-Low
Vinl =  0.700V
Vinh =  1.700V
Vmeas =  1.250V
Cref =  0.0F
Rref =  1.000M
Vref =  0.0V
C_comp   2.000pF   1.500pF   2.500pF
[Temperature Range]   25.000   0.125k   -40.000
[Voltage Range]   2.500V   2.430V   2.580V
[C Comp Corner]
C_comp   2.000pF   1.500pF   2.500pF
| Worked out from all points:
|   slope of the pulldown table from 0 to 0.375 V, typ, clamps not added: 101 ohm
|   slope of the pullup table from 0 to 0.375 V, typ, clamps not added: 101 ohm
|   GND clamp passes 1 mA (typ) near -0.53 V on its own axis
|   POWER clamp passes 1 mA (typ) near -0.42 V on its own axis
|   rising waveform, R_fixture 50.000, V_fixture 0.000: 20-80 % time 173ps typ, 211ps min, 149ps max; typ from 0 V to 0.832 V
|   rising waveform, R_fixture 50.000, V_fixture 2.500: 20-80 % time 133ps typ, 156ps min, 116ps max; typ from 1.67 V to 2.5 V
|   falling waveform, R_fixture 50.000, V_fixture 2.500: 20-80 % time 154ps typ, 183ps min, 137ps max; typ from 2.5 V to 1.67 V
|   falling waveform, R_fixture 50.000, V_fixture 0.000: 20-80 % time 131ps typ, 146ps min, 122ps max; typ from 0.832 V to 0 V
[Pulldown]
|Voltage   I(typ)   I(min)   I(max)
-2.5V     -1.026mA   -903.5uA   -1.21mA
-1.284V   -1.838mA   -1.659mA   -2.096mA
-980mV    -5.631mA   -4.103mA   -7.38mA
-524mV    -4.941mA   -4.114mA   -6.055mA
2.288V    22.69mA    19.21mA    27.85mA
3.048V    27.71mA    22.24mA    34.79mA
3.352V    26.96mA    17.1mA     34.45mA
3.504V    19.46mA    9.065mA    33.61mA
3.58V     12.67mA    6.797mA    29.81mA
3.732V    6.503mA    4.532mA    11.46mA
3.884V    4.504mA    3.498mA    6.252mA
5V        2.145mA    1.865mA    2.674mA
[Pullup]
|Voltage   I(typ)   I(min)   I(max)
-2.5V     513.3uA    473.2uA    538uA
-1.232V   1.365mA    1.223mA    1.55mA
-928mV    4.971mA    3.518mA    6.37mA
-396mV    3.724mA    3.071mA    4.557mA
3.1V      -28.6mA    -25.92mA   -36.36mA
3.328V    -31.55mA   -25.06mA   -39.11mA
3.48V     -29.28mA   -16.73mA   -39.54mA
3.556V    -22.44mA   -12.58mA   -38.93mA
3.632V    -15.34mA   -9.966mA   -32.82mA
3.708V    -11.42mA   -8.38mA    -20.87mA
3.86V     -8.047mA   -6.653mA   -11.06mA
5V        -4.842mA   -4.193mA   -5.904mA
[GND_clamp]
|Voltage   I(typ)   I(min)   I(max)
-2.5V     -1.176A    -1.175A    -1.18A
-1.072V   -43.15mA   -59.89mA   -34.87mA
-1.021V   -25.5mA    -38.75mA   -21.15mA
-970mV    -15.94mA   -23.91mA   -15.48mA
-919mV    -11.55mA   -15.09mA   -12.8mA
-868mV    -9.208mA   -10.36mA   -10.81mA
-817mV    -7.507mA   -7.725mA   -8.99mA
-715mV    -4.652mA   -4.658mA   -5.6mA
-562mV    -1.396mA   -1.715mA   -1.585mA
-460mV    -331.3uA   -573.9uA   -320.1uA
-1mV      -317.6nA   -575.7nA   -335.3nA
2.5V      19.47nA    0A         -24.11uA
[POWER_clamp]
|Voltage   I(typ)   I(min)   I(max)
-2.498V   1.294A     1.303A     1.292A
-1.121V   95.14mA    121.6mA    80.07mA
-1.07V    64.33mA    89.71mA    50.75mA
-1.019V   40.02mA    62.12mA    30.84mA
-968mV    24.3mA     40.21mA    21.31mA
-917mV    16.34mA    25.01mA    17.39mA
-866mV    12.64mA    16mA       15.07mA
-815mV    10.49mA    11.15mA    13.11mA
-662mV    5.902mA    5.367mA    7.663mA
-407mV    768.2uA    1.002mA    960.5uA
-152mV    40.9uA     39.04uA    48.9uA
2.5V      0A         0A         24.96uA
[Ramp]
| variable   typ   min   max
dV/dt_r   0.510/0.174n   0.441/0.212n   0.602/0.150n
dV/dt_f   0.511/0.155n   0.446/0.185n   0.601/0.137n
R_load = 50.000
[Rising Waveform]
R_fixture = 50.000
V_fixture = 0.000
V_fixture_min = 0.000
V_fixture_max = 0.000
|  time   V(typ)   V(min)   V(max)
0s        9.948uV    -75.96uV   -34.58uV
454ps     -831.2uV   -355uV     8.361mV
494ps     -2.67mV    -261.4uV   98.36mV
568ps     5.708mV    -1.679mV   451.3mV
668ps     255.4mV    -2.112mV   789.1mV
749ps     531.8mV    73.17mV    891.8mV
817ps     667.7mV    228.9mV    933.1mV
968ps     783.9mV    545.4mV    968.1mV
1.148ns   818.3mV    669.7mV    977.7mV
50ns      832.5mV    719mV      983.1mV
[Rising Waveform]
R_fixture = 50.000
V_fixture = 2.500
V_fixture_min = 2.430
V_fixture_max = 2.580
|  time   V(typ)   V(min)   V(max)
0s        1.665V     1.702V     1.599V
429ps     1.666V     1.703V     1.618V
465ps     1.665V     1.703V     1.733V
539ps     1.709V     1.703V     2.215V
611ps     2.006V     1.714V     2.422V
692ps     2.301V     1.882V     2.51V
770ps     2.407V     2.149V     2.545V
829ps     2.444V     2.273V     2.558V
1.109ns   2.493V     2.413V     2.576V
50ns      2.5V       2.43V      2.58V
[Falling Waveform]
R_fixture = 50.000
V_fixture = 2.500
V_fixture_min = 2.430
V_fixture_max = 2.580
|  time   V(typ)   V(min)   V(max)
0s        2.5V       2.43V      2.58V
471ps     2.501V     2.43V      2.535V
531ps     2.493V     2.43V      2.414V
622ps     2.405V     2.428V     1.951V
668ps     2.273V     2.411V     1.81V
755ps     1.936V     2.326V     1.691V
834ps     1.795V     2.12V      1.647V
978ps     1.707V     1.828V     1.616V
1.228ns   1.675V     1.726V     1.603V
50ns      1.665V     1.702V     1.599V
[Falling Waveform]
R_fixture = 50.000
V_fixture = 0.000
V_fixture_min = 0.000
V_fixture_max = 0.000
|  time   V(typ)   V(min)   V(max)
0s        832.5mV    719mV      983.1mV
453ps     832.8mV    718.8mV    948mV
501ps     831mV      718.8mV    833.3mV
582ps     768.9mV    719.1mV    357.9mV
655ps     487.8mV    699.5mV    154.1mV
713ps     247.8mV    628.3mV    83.62mV
791ps     110.6mV    362.2mV    37.86mV
903ps     37.84mV    115.6mV    12.63mV
1.103ns   6.093mV    19.07mV    1.965mV
50ns      9.948uV    -75.96uV   -34.58uV
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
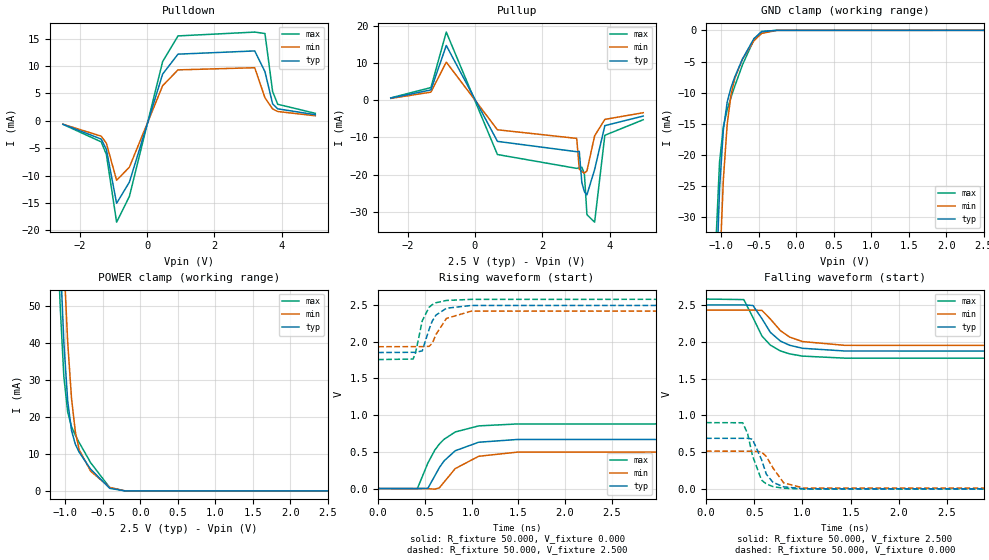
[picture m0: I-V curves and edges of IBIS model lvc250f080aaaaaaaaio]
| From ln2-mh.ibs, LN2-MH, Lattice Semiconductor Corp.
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|   Model lvc250f080aaaaaaaaio
[Model] lvc250f080aaaaaaaaio
Model_type I/O
Polarity   Non-Inverting
Enable   Active-Low
Vinl =  0.700V
Vinh =  1.700V
Vmeas =  1.250V
Cref =  0.0F
Rref =  1.000M
Vref =  0.0V
C_comp   2.000pF   1.500pF   2.500pF
[Temperature Range]   25.000   0.125k   -40.000
[Voltage Range]   2.500V   2.430V   2.580V
[C Comp Corner]
C_comp   2.000pF   1.500pF   2.500pF
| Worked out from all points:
|   slope of the pulldown table from 0 to 0.375 V, typ, clamps not added: 52.4 ohm
|   slope of the pullup table from 0 to 0.375 V, typ, clamps not added: 52 ohm
|   GND clamp passes 1 mA (typ) near -0.54 V on its own axis
|   POWER clamp passes 1 mA (typ) near -0.43 V on its own axis
|   rising waveform, R_fixture 50.000, V_fixture 0.000: 20-80 % time 284ps typ, 295ps min, 277ps max; typ from 0 V to 0.69 V
|   rising waveform, R_fixture 50.000, V_fixture 2.500: 20-80 % time 123ps typ, 147ps min, 102ps max; typ from 1.85 V to 2.5 V
|   falling waveform, R_fixture 50.000, V_fixture 2.500: 20-80 % time 261ps typ, 276ps min, 249ps max; typ from 2.5 V to 1.85 V
|   falling waveform, R_fixture 50.000, V_fixture 0.000: 20-80 % time 121ps typ, 141ps min, 106ps max; typ from 0.69 V to 0 V
[Pulldown]
|Voltage   I(typ)   I(min)   I(max)
-2.5V     -629.9uA   -619.8uA   -639.9uA
-1.36V    -3.341mA   -2.807mA   -3.849mA
-1.208V   -5.224mA   -4.097mA   -6.154mA
-904mV    -15.06mA   -10.86mA   -18.51mA
-524mV    -11.19mA   -8.46mA    -13.8mA
464mV     8.532mA    6.406mA    10.82mA
920mV     12.17mA    9.3mA      15.5mA
3.2V      12.76mA    9.695mA    16.2mA
3.504V    8.967mA    4.203mA    15.94mA
3.732V    3.097mA    2.171mA    5.335mA
3.884V    2.188mA    1.698mA    3.022mA
5V        1.12mA     922.4uA    1.367mA
[Pullup]
|Voltage   I(typ)   I(min)   I(max)
-2.5V     564.9uA    479uA      626.8uA
-1.308V   2.77mA     2.169mA    3.404mA
-852mV    14.72mA    10.25mA    18.33mA
668mV     -11.08mA   -7.961mA   -14.62mA
3.024V    -13.86mA   -10.28mA   -18.35mA
3.1V      -13.78mA   -18.53mA   -18.18mA
3.176V    -22.17mA   -19.24mA   -18.03mA
3.252V    -24.61mA   -19.61mA   -19.87mA
3.328V    -25.46mA   -19.04mA   -30.79mA
3.556V    -18.67mA   -9.588mA   -32.83mA
3.86V     -6.84mA    -5.164mA   -9.438mA
5V        -4.27mA    -3.37mA    -5.263mA
[GND_clamp]
|Voltage   I(typ)   I(min)   I(max)
-2.5V     -1.176A    -1.175A    -1.18A
-1.072V   -43.12mA   -59.87mA   -34.84mA
-1.021V   -25.46mA   -38.72mA   -21.1mA
-970mV    -15.9mA    -23.88mA   -15.42mA
-919mV    -11.5mA    -15.05mA   -12.74mA
-868mV    -9.155mA   -10.31mA   -10.74mA
-817mV    -7.451mA   -7.678mA   -8.924mA
-715mV    -4.588mA   -4.605mA   -5.525mA
-562mV    -1.31mA    -1.648mA   -1.483mA
-460mV    -221.2uA   -492.9uA   -183.3uA
-256mV    -336.9nA   -5.429uA   -53.89nA
2.5V      0A         0A         0A
[POWER_clamp]
|Voltage   I(typ)   I(min)   I(max)
-2.498V   1.294A     1.303A     1.292A
-1.121V   95.13mA    121.6mA    80.05mA
-1.07V    64.31mA    89.69mA    50.73mA
-1.019V   40mA       62.1mA     30.81mA
-968mV    24.27mA    40.19mA    21.27mA
-917mV    16.31mA    24.99mA    17.34mA
-866mV    12.6mA     15.97mA    15.03mA
-815mV    10.45mA    11.12mA    13.06mA
-662mV    5.856mA    5.328mA    7.611mA
-407mV    698.4uA    949.4uA    879.7uA
-203mV    1.851uA    18.03uA    575.7nA
2.5V      0A         0A         0A
[Ramp]
| variable   typ   min   max
dV/dt_r   0.425/0.282n   0.317/0.295n   0.555/0.276n
dV/dt_f   0.399/0.260n   0.308/0.277n   0.506/0.249n
R_load = 50.000
[Rising Waveform]
R_fixture = 50.000
V_fixture = 0.000
V_fixture_min = 0.000
V_fixture_max = 0.000
|  time   V(typ)   V(min)   V(max)
0s        44.96uV    51.71uV    40.29uV
419ps     -18.97uV   -270.7uV   -3.171mV
532ps     2.232mV    -1.35mV    346.8mV
607ps     173.9mV    -8.774mV   524.5mV
656ps     286.6mV    10.55mV    606.7mV
707ps     377.9mV    89.92mV    672mV
825ps     514.3mV    271.1mV    770mV
1.076ns   630.3mV    439mV      852.9mV
1.487ns   667.6mV    495.2mV    879mV
50ns      690.2mV    515.7mV    902.9mV
[Rising Waveform]
R_fixture = 50.000
V_fixture = 2.500
V_fixture_min = 2.430
V_fixture_max = 2.580
|  time   V(typ)   V(min)   V(max)
0s        1.852V     1.931V     1.756V
373ps     1.855V     1.932V     1.763V
398ps     1.855V     1.932V     1.833V
472ps     1.874V     1.933V     2.284V
545ps     2.168V     1.936V     2.468V
579ps     2.28V      1.977V     2.504V
619ps     2.362V     2.098V     2.53V
731ps     2.455V     2.317V     2.561V
999ps     2.493V     2.416V     2.576V
50ns      2.5V       2.43V      2.58V
[Falling Waveform]
R_fixture = 50.000
V_fixture = 2.500
V_fixture_min = 2.430
V_fixture_max = 2.580
|  time   V(typ)   V(min)   V(max)
0s        2.5V       2.43V      2.58V
391ps     2.5V       2.43V      2.573V
486ps     2.493V     2.43V      2.33V
580ps     2.313V     2.426V     2.077V
667ps     2.128V     2.309V     1.955V
771ps     2.01V      2.152V     1.876V
867ps     1.953V     2.064V     1.836V
1.001ns   1.912V     2.003V     1.806V
1.441ns   1.875V     1.952V     1.778V
50ns      1.852V     1.931V     1.756V
[Falling Waveform]
R_fixture = 50.000
V_fixture = 0.000
V_fixture_min = 0.000
V_fixture_max = 0.000
|  time   V(typ)   V(min)   V(max)
0s        690.2mV    515.7mV    902.9mV
380ps     689.9mV    515.4mV    901.3mV
432ps     690.5mV    515.4mV    749.5mV
481ps     677.9mV    515.2mV    457.8mV
575ps     401.7mV    506.5mV    123.2mV
626ps     201.5mV    441.1mV    69.77mV
695ps     91.46mV    285.4mV    34.69mV
806ps     31.69mV    84.45mV    12.25mV
1.015ns   5.257mV    14.39mV    1.962mV
50ns      44.96uV    51.71uV    40.29uV
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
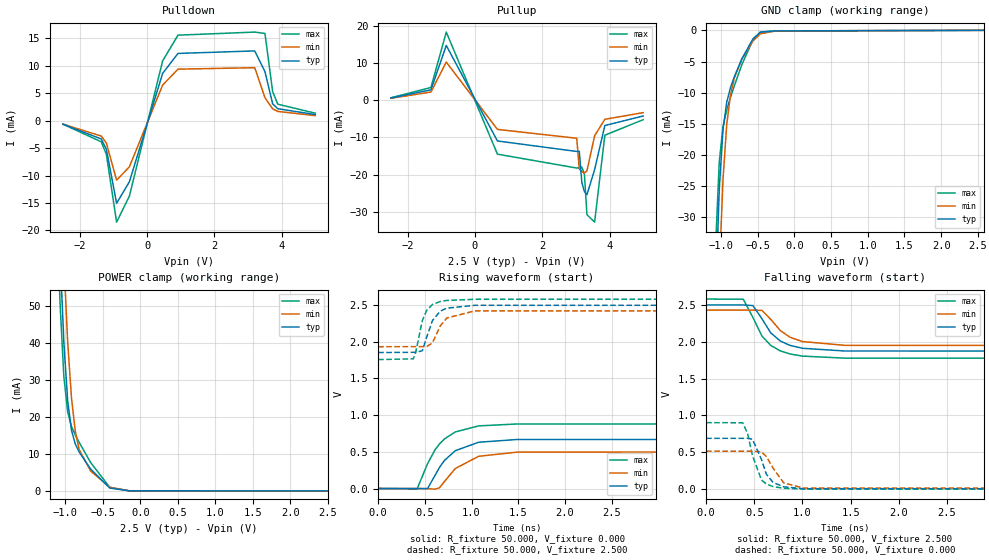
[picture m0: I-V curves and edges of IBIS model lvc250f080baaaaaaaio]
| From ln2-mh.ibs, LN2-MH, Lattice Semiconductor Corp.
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|   Model lvc250f080baaaaaaaio
[Model] lvc250f080baaaaaaaio
Model_type I/O
Polarity   Non-Inverting
Enable   Active-Low
Vinl =  0.700V
Vinh =  1.700V
Vmeas =  1.250V
Cref =  0.0F
Rref =  1.000M
Vref =  0.0V
C_comp   2.000pF   1.500pF   2.500pF
[Temperature Range]   25.000   0.125k   -40.000
[Voltage Range]   2.500V   2.430V   2.580V
[C Comp Corner]
C_comp   2.000pF   1.500pF   2.500pF
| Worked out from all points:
|   slope of the pulldown table from 0 to 0.375 V, typ, clamps not added: 52.4 ohm
|   slope of the pullup table from 0 to 0.375 V, typ, clamps not added: 52.6 ohm
|   GND clamp passes 1 mA (typ) near -0.53 V on its own axis
|   POWER clamp passes 1 mA (typ) near -0.42 V on its own axis
|   rising waveform, R_fixture 50.000, V_fixture 0.000: 20-80 % time 284ps typ, 295ps min, 277ps max; typ from 0 V to 0.69 V
|   rising waveform, R_fixture 50.000, V_fixture 2.500: 20-80 % time 123ps typ, 147ps min, 103ps max; typ from 1.85 V to 2.5 V
|   falling waveform, R_fixture 50.000, V_fixture 2.500: 20-80 % time 261ps typ, 276ps min, 249ps max; typ from 2.5 V to 1.85 V
|   falling waveform, R_fixture 50.000, V_fixture 0.000: 20-80 % time 121ps typ, 141ps min, 106ps max; typ from 0.69 V to 0 V
[Pulldown]
|Voltage   I(typ)   I(min)   I(max)
-2.5V     -628.6uA   -618.3uA   -638.7uA
-1.36V    -3.338mA   -2.803mA   -3.847mA
-1.208V   -5.22mA    -4.093mA   -6.151mA
-904mV    -15.05mA   -10.84mA   -18.5mA
-524mV    -11.13mA   -8.409mA   -13.74mA
464mV     8.625mA    6.499mA    10.91mA
920mV     12.26mA    9.392mA    15.59mA
3.2V      12.72mA    9.659mA    16.15mA
3.504V    8.942mA    4.189mA    15.9mA
3.732V    3.089mA    2.164mA    5.322mA
3.884V    2.182mA    1.692mA    3.014mA
5V        1.117mA    919.8uA    1.364mA
[Pullup]
|Voltage   I(typ)   I(min)   I(max)
-2.5V     561.9uA    476.2uA    623.6uA
-1.308V   2.763mA    2.162mA    3.396mA
-852mV    14.68mA    10.22mA    18.28mA
668mV     -10.98mA   -7.87mA    -14.52mA
3.024V    -13.8mA    -10.25mA   -18.26mA
3.1V      -13.74mA   -18.5mA    -18.12mA
3.176V    -22.14mA   -19.21mA   -18mA
3.252V    -24.59mA   -19.59mA   -19.85mA
3.328V    -25.44mA   -19.02mA   -30.77mA
3.556V    -18.66mA   -9.582mA   -32.81mA
3.86V     -6.838mA   -5.161mA   -9.435mA
5V        -4.268mA   -3.368mA   -5.262mA
[GND_clamp]
|Voltage   I(typ)   I(min)   I(max)
-2.5V     -1.176A    -1.175A    -1.18A
-1.072V   -43.12mA   -59.88mA   -34.84mA
-1.021V   -25.47mA   -38.73mA   -21.11mA
-970mV    -15.91mA   -23.89mA   -15.44mA
-919mV    -11.52mA   -15.06mA   -12.75mA
-868mV    -9.172mA   -10.33mA   -10.76mA
-817mV    -7.47mA    -7.698mA   -8.941mA
-715mV    -4.614mA   -4.632mA   -5.549mA
-562mV    -1.356mA   -1.692mA   -1.528mA
-460mV    -296.7uA   -557.9uA   -261.8uA
-256mV    -93.15uA   -97.62uA   -93.76uA
2.58V     0A         0A         0A
[POWER_clamp]
|Voltage   I(typ)   I(min)   I(max)
-2.498V   1.294A     1.303A     1.292A
-1.121V   95.14mA    121.6mA    80.07mA
-1.07V    64.33mA    89.71mA    50.75mA
-1.019V   40.02mA    62.12mA    30.84mA
-968mV    24.3mA     40.21mA    21.31mA
-917mV    16.34mA    25.01mA    17.39mA
-866mV    12.64mA    16mA       15.07mA
-815mV    10.49mA    11.15mA    13.11mA
-662mV    5.902mA    5.367mA    7.663mA
-407mV    768.2uA    1.002mA    960.5uA
-152mV    40.9uA     39.04uA    48.9uA
2.5V      0A         0A         0A
[Ramp]
| variable   typ   min   max
dV/dt_r   0.425/0.282n   0.317/0.293n   0.555/0.276n
dV/dt_f   0.399/0.260n   0.308/0.275n   0.506/0.249n
R_load = 50.000
[Rising Waveform]
R_fixture = 50.000
V_fixture = 0.000
V_fixture_min = 0.000
V_fixture_max = 0.000
|  time   V(typ)   V(min)   V(max)
0s        43.84uV    51.54uV    40.52uV
417ps     -26.74uV   -270uV     -4.713mV
528ps     -1.841mV   -986.3uV   335.2mV
609ps     179.1mV    -8.71mV    528.3mV
657ps     288.8mV    11.64mV    608.1mV
711ps     384.2mV    97.08mV    676.4mV
826ps     515.1mV    272.3mV    770.6mV
1.076ns   630.3mV    439mV      852.9mV
1.487ns   667.6mV    495.2mV    879mV
50ns      690.2mV    515.7mV    902.9mV
[Rising Waveform]
R_fixture = 50.000
V_fixture = 2.500
V_fixture_min = 2.430
V_fixture_max = 2.580
|  time   V(typ)   V(min)   V(max)
0s        1.852V     1.931V     1.756V
376ps     1.855V     1.932V     1.766V
402ps     1.855V     1.932V     1.855V
473ps     1.876V     1.933V     2.288V
520ps     2.063V     1.933V     2.427V
581ps     2.286V     1.983V     2.506V
665ps     2.416V     2.215V     2.547V
735ps     2.456V     2.322V     2.561V
1.035ns   2.495V     2.419V     2.577V
50ns      2.5V       2.43V      2.58V
[Falling Waveform]
R_fixture = 50.000
V_fixture = 2.500
V_fixture_min = 2.430
V_fixture_max = 2.580
|  time   V(typ)   V(min)   V(max)
0s        2.5V       2.43V      2.58V
386ps     2.5V       2.43V      2.578V
486ps     2.492V     2.43V      2.33V
580ps     2.312V     2.426V     2.077V
671ps     2.121V     2.304V     1.951V
771ps     2.01V      2.152V     1.876V
871ps     1.951V     2.062V     1.835V
1.001ns   1.912V     2.003V     1.806V
1.441ns   1.875V     1.952V     1.778V
50ns      1.852V     1.931V     1.756V
[Falling Waveform]
R_fixture = 50.000
V_fixture = 0.000
V_fixture_min = 0.000
V_fixture_max = 0.000
|  time   V(typ)   V(min)   V(max)
0s        690.2mV    515.7mV    902.9mV
380ps     689.9mV    515.4mV    901.3mV
432ps     690.5mV    515.4mV    749.5mV
481ps     677.9mV    515.2mV    457.8mV
575ps     401.7mV    506.6mV    123.2mV
626ps     201.5mV    441.3mV    69.77mV
695ps     91.46mV    285.6mV    34.69mV
806ps     31.69mV    84.5mV     12.25mV
1.015ns   5.256mV    14.4mV     1.962mV
50ns      43.84uV    51.54uV    40.52uV
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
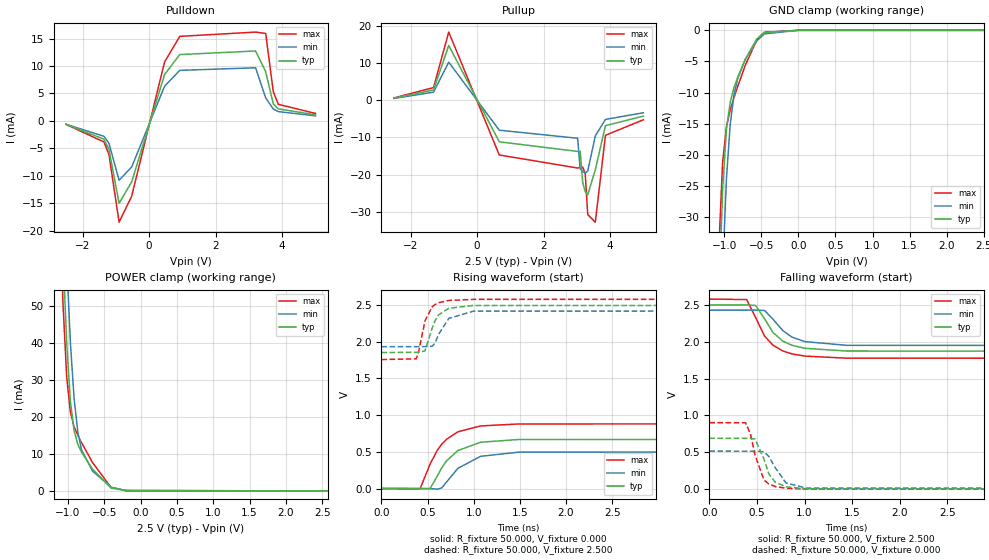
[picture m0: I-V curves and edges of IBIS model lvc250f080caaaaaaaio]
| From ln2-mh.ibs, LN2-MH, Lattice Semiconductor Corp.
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|   Model lvc250f080caaaaaaaio
[Model] lvc250f080caaaaaaaio
Model_type I/O
Polarity   Non-Inverting
Enable   Active-Low
Vinl =  0.700V
Vinh =  1.700V
Vmeas =  1.250V
Cref =  0.0F
Rref =  1.000M
Vref =  0.0V
C_comp   2.000pF   1.500pF   2.500pF
[Temperature Range]   25.000   0.125k   -40.000
[Voltage Range]   2.500V   2.430V   2.580V
[C Comp Corner]
C_comp   2.000pF   1.500pF   2.500pF
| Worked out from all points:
|   slope of the pulldown table from 0 to 0.375 V, typ, clamps not added: 53 ohm
|   slope of the pullup table from 0 to 0.375 V, typ, clamps not added: 52 ohm
|   GND clamp passes 1 mA (typ) near -0.53 V on its own axis
|   POWER clamp passes 1 mA (typ) near -0.43 V on its own axis
|   rising waveform, R_fixture 50.000, V_fixture 0.000: 20-80 % time 284ps typ, 295ps min, 277ps max; typ from 0 V to 0.69 V
|   rising waveform, R_fixture 50.000, V_fixture 2.500: 20-80 % time 123ps typ, 147ps min, 103ps max; typ from 1.85 V to 2.5 V
|   falling waveform, R_fixture 50.000, V_fixture 2.500: 20-80 % time 261ps typ, 276ps min, 249ps max; typ from 2.5 V to 1.85 V
|   falling waveform, R_fixture 50.000, V_fixture 0.000: 20-80 % time 121ps typ, 141ps min, 106ps max; typ from 0.69 V to 0 V
[Pulldown]
|Voltage   I(typ)   I(min)   I(max)
-2.5V     -623.3uA   -614uA     -632.2uA
-1.36V    -3.33mA    -2.796mA   -3.837mA
-1.208V   -5.208mA   -4.083mA   -6.136mA
-904mV    -15.01mA   -10.81mA   -18.45mA
-524mV    -11.09mA   -8.388mA   -13.69mA
464mV     8.444mA    6.322mA    10.73mA
920mV     12.08mA    9.209mA    15.4mA
3.2V      12.74mA    9.676mA    16.18mA
3.504V    8.959mA    4.197mA    15.93mA
3.732V    3.095mA    2.168mA    5.332mA
3.884V    2.186mA    1.695mA    3.02mA
5V        1.119mA    921.4uA    1.367mA
[Pullup]
|Voltage   I(typ)   I(min)   I(max)
-2.5V     564.1uA    478uA      626.1uA
-1.308V   2.768mA    2.166mA    3.402mA
-852mV    14.71mA    10.23mA    18.31mA
668mV     -11.17mA   -8.052mA   -14.71mA
3.024V    -13.76mA   -10.22mA   -18.21mA
3.1V      -13.7mA    -18.47mA   -18.06mA
3.176V    -22.1mA    -19.19mA   -17.94mA
3.252V    -24.55mA   -19.56mA   -19.79mA
3.328V    -25.4mA    -19mA      -30.72mA
3.556V    -18.64mA   -9.57mA    -32.77mA
3.86V     -6.829mA   -5.154mA   -9.423mA
5V        -4.263mA   -3.364mA   -5.255mA
[GND_clamp]
|Voltage   I(typ)   I(min)   I(max)
-2.5V     -1.176A    -1.175A    -1.18A
-1.072V   -43.15mA   -59.89mA   -34.87mA
-1.021V   -25.5mA    -38.75mA   -21.15mA
-970mV    -15.94mA   -23.91mA   -15.48mA
-919mV    -11.55mA   -15.09mA   -12.8mA
-868mV    -9.208mA   -10.36mA   -10.81mA
-817mV    -7.507mA   -7.725mA   -8.99mA
-715mV    -4.652mA   -4.658mA   -5.6mA
-562mV    -1.396mA   -1.715mA   -1.585mA
-460mV    -331.3uA   -573.9uA   -320.1uA
-1mV      -317.6nA   -575.7nA   -335.3nA
2.5V      0A         0A         0A
[POWER_clamp]
|Voltage   I(typ)   I(min)   I(max)
-2.498V   1.294A     1.303A     1.292A
-1.121V   95.13mA    121.6mA    80.05mA
-1.07V    64.32mA    89.7mA     50.73mA
-1.019V   40.01mA    62.11mA    30.82mA
-968mV    24.28mA    40.2mA     21.28mA
-917mV    16.32mA    25mA       17.36mA
-866mV    12.61mA    15.98mA    15.04mA
-815mV    10.46mA    11.14mA    13.07mA
-662mV    5.878mA    5.353mA    7.63mA
-407mV    756.4uA    1.004mA    934.2uA
-203mV    93.32uA    107.9uA    92.71uA
2.58V     0A         0A         0A
[Ramp]
| variable   typ   min   max
dV/dt_r   0.425/0.282n   0.317/0.293n   0.555/0.276n
dV/dt_f   0.399/0.260n   0.308/0.277n   0.506/0.249n
R_load = 50.000
[Rising Waveform]
R_fixture = 50.000
V_fixture = 0.000
V_fixture_min = 0.000
V_fixture_max = 0.000
|  time   V(typ)   V(min)   V(max)
0s        49.18uV    -16.64uV   14.36uV
419ps     -6.967uV   -339.1uV   -3.197mV
526ps     -3.23mV    -893.5uV   329.3mV
606ps     171.9mV    -8.825mV   522.6mV
654ps     283mV      8.301mV    603.6mV
708ps     379.8mV    91.69mV    673.1mV
828ps     517mV      274.6mV    771.8mV
1.074ns   629.9mV    438.3mV    852.5mV
1.487ns   667.6mV    495.1mV    879mV
50ns      690.2mV    515.7mV    902.9mV
[Rising Waveform]
R_fixture = 50.000
V_fixture = 2.500
V_fixture_min = 2.430
V_fixture_max = 2.580
|  time   V(typ)   V(min)   V(max)
0s        1.852V     1.931V     1.756V
376ps     1.855V     1.932V     1.766V
402ps     1.855V     1.932V     1.855V
472ps     1.874V     1.933V     2.284V
549ps     2.183V     1.937V     2.473V
579ps     2.28V      1.977V     2.504V
621ps     2.366V     2.103V     2.531V
731ps     2.455V     2.317V     2.561V
999ps     2.493V     2.416V     2.576V
50ns      2.5V       2.43V      2.58V
[Falling Waveform]
R_fixture = 50.000
V_fixture = 2.500
V_fixture_min = 2.430
V_fixture_max = 2.580
|  time   V(typ)   V(min)   V(max)
0s        2.5V       2.43V      2.58V
391ps     2.5V       2.43V      2.573V
486ps     2.493V     2.43V      2.33V
580ps     2.313V     2.425V     2.077V
667ps     2.128V     2.309V     1.955V
771ps     2.01V      2.152V     1.876V
867ps     1.953V     2.064V     1.836V
1.001ns   1.912V     2.003V     1.806V
1.441ns   1.875V     1.952V     1.778V
50ns      1.852V     1.931V     1.756V
[Falling Waveform]
R_fixture = 50.000
V_fixture = 0.000
V_fixture_min = 0.000
V_fixture_max = 0.000
|  time   V(typ)   V(min)   V(max)
0s        690.2mV    515.7mV    902.9mV
380ps     689.9mV    515.4mV    901.1mV
432ps     690.5mV    515.4mV    748.4mV
480ps     679.9mV    515.2mV    462.9mV
574ps     407.2mV    507.4mV    124.3mV
625ps     204.6mV    442.7mV    70.26mV
695ps     91.62mV    285.7mV    34.58mV
805ps     32.04mV    85.27mV    12.3mV
1.015ns   5.269mV    14.34mV    1.932mV
50ns      49.18uV    -16.64uV   14.36uV
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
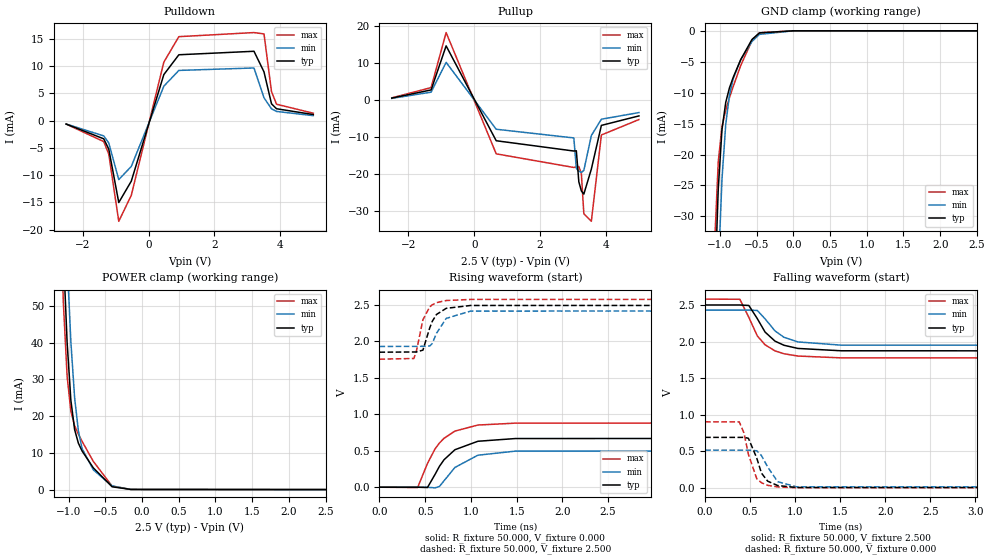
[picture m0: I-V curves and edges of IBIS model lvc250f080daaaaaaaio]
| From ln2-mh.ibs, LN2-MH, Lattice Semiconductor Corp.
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|   Model lvc250f080daaaaaaaio
[Model] lvc250f080daaaaaaaio
Model_type I/O
Polarity   Non-Inverting
Enable   Active-Low
Vinl =  0.700V
Vinh =  1.700V
Vmeas =  1.250V
Cref =  0.0F
Rref =  1.000M
Vref =  0.0V
C_comp   2.000pF   1.500pF   2.500pF
[Temperature Range]   25.000   0.125k   -40.000
[Voltage Range]   2.500V   2.430V   2.580V
[C Comp Corner]
C_comp   2.000pF   1.500pF   2.500pF
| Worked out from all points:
|   slope of the pulldown table from 0 to 0.375 V, typ, clamps not added: 53 ohm
|   slope of the pullup table from 0 to 0.375 V, typ, clamps not added: 52.6 ohm
|   GND clamp passes 1 mA (typ) near -0.53 V on its own axis
|   POWER clamp passes 1 mA (typ) near -0.42 V on its own axis
|   rising waveform, R_fixture 50.000, V_fixture 0.000: 20-80 % time 284ps typ, 295ps min, 277ps max; typ from 0 V to 0.69 V
|   rising waveform, R_fixture 50.000, V_fixture 2.500: 20-80 % time 122ps typ, 147ps min, 103ps max; typ from 1.85 V to 2.5 V
|   falling waveform, R_fixture 50.000, V_fixture 2.500: 20-80 % time 261ps typ, 276ps min, 249ps max; typ from 2.5 V to 1.85 V
|   falling waveform, R_fixture 50.000, V_fixture 0.000: 20-80 % time 121ps typ, 141ps min, 106ps max; typ from 0.69 V to 0 V
[Pulldown]
|Voltage   I(typ)   I(min)   I(max)
-2.5V     -623.3uA   -614uA     -632.2uA
-1.36V    -3.33mA    -2.796mA   -3.837mA
-1.208V   -5.208mA   -4.083mA   -6.136mA
-904mV    -15.01mA   -10.81mA   -18.45mA
-524mV    -11.09mA   -8.388mA   -13.69mA
464mV     8.444mA    6.322mA    10.73mA
920mV     12.08mA    9.209mA    15.4mA
3.2V      12.72mA    9.659mA    16.15mA
3.504V    8.942mA    4.189mA    15.9mA
3.732V    3.089mA    2.164mA    5.322mA
3.884V    2.182mA    1.692mA    3.014mA
5V        1.117mA    919.8uA    1.364mA
[Pullup]
|Voltage   I(typ)   I(min)   I(max)
-2.5V     561.9uA    476.2uA    623.6uA
-1.308V   2.763mA    2.162mA    3.396mA
-852mV    14.68mA    10.22mA    18.28mA
668mV     -10.98mA   -7.87mA    -14.52mA
3.024V    -13.76mA   -10.22mA   -18.21mA
3.1V      -13.7mA    -18.47mA   -18.06mA
3.176V    -22.1mA    -19.19mA   -17.94mA
3.252V    -24.55mA   -19.56mA   -19.79mA
3.328V    -25.4mA    -19mA      -30.72mA
3.556V    -18.64mA   -9.57mA    -32.77mA
3.86V     -6.829mA   -5.154mA   -9.423mA
5V        -4.263mA   -3.364mA   -5.255mA
[GND_clamp]
|Voltage   I(typ)   I(min)   I(max)
-2.5V     -1.176A    -1.175A    -1.18A
-1.072V   -43.15mA   -59.89mA   -34.87mA
-1.021V   -25.5mA    -38.75mA   -21.15mA
-970mV    -15.94mA   -23.91mA   -15.48mA
-919mV    -11.55mA   -15.09mA   -12.8mA
-868mV    -9.208mA   -10.36mA   -10.81mA
-817mV    -7.507mA   -7.725mA   -8.99mA
-715mV    -4.652mA   -4.658mA   -5.6mA
-562mV    -1.396mA   -1.715mA   -1.585mA
-460mV    -331.3uA   -573.9uA   -320.1uA
-1mV      -317.6nA   -575.7nA   -335.3nA
2.5V      19.47nA    0A         -24.11uA
[POWER_clamp]
|Voltage   I(typ)   I(min)   I(max)
-2.498V   1.294A     1.303A     1.292A
-1.121V   95.14mA    121.6mA    80.07mA
-1.07V    64.33mA    89.71mA    50.75mA
-1.019V   40.02mA    62.12mA    30.84mA
-968mV    24.3mA     40.21mA    21.31mA
-917mV    16.34mA    25.01mA    17.39mA
-866mV    12.64mA    16mA       15.07mA
-815mV    10.49mA    11.15mA    13.11mA
-662mV    5.902mA    5.367mA    7.663mA
-407mV    768.2uA    1.002mA    960.5uA
-152mV    40.9uA     39.04uA    48.9uA
2.5V      0A         0A         24.96uA
[Ramp]
| variable   typ   min   max
dV/dt_r   0.425/0.282n   0.317/0.295n   0.555/0.276n
dV/dt_f   0.399/0.260n   0.308/0.275n   0.506/0.249n
R_load = 50.000
[Rising Waveform]
R_fixture = 50.000
V_fixture = 0.000
V_fixture_min = 0.000
V_fixture_max = 0.000
|  time   V(typ)   V(min)   V(max)
0s        49.18uV    -16.64uV   14.36uV
417ps     -16.43uV   -338.1uV   -4.739mV
525ps     -4.008mV   -834.1uV   326.3mV
607ps     174.4mV    -8.837mV   524.5mV
656ps     287.1mV    10.55mV    606.7mV
706ps     376.7mV    88.18mV    670.9mV
825ps     514.4mV    271.2mV    770mV
1.076ns   630.3mV    439mV      852.9mV
1.486ns   667.6mV    495.1mV    879mV
50ns      690.2mV    515.7mV    902.9mV
[Rising Waveform]
R_fixture = 50.000
V_fixture = 2.500
V_fixture_min = 2.430
V_fixture_max = 2.580
|  time   V(typ)   V(min)   V(max)
0s        1.852V     1.931V     1.756V
376ps     1.855V     1.932V     1.766V
402ps     1.855V     1.932V     1.855V
475ps     1.88V      1.933V     2.296V
549ps     2.183V     1.937V     2.473V
577ps     2.275V     1.972V     2.502V
624ps     2.37V      2.112V     2.532V
730ps     2.454V     2.316V     2.561V
997ps     2.493V     2.416V     2.576V
50ns      2.5V       2.43V      2.58V
[Falling Waveform]
R_fixture = 50.000
V_fixture = 2.500
V_fixture_min = 2.430
V_fixture_max = 2.580
|  time   V(typ)   V(min)   V(max)
0s        2.5V       2.43V      2.58V
386ps     2.5V       2.43V      2.578V
486ps     2.493V     2.43V      2.33V
580ps     2.313V     2.425V     2.077V
666ps     2.13V      2.311V     1.956V
776ps     2.006V     2.146V     1.873V
877ps     1.949V     2.058V     1.833V
1.031ns   1.906V     1.995V     1.802V
1.51ns    1.874V     1.951V     1.777V
50ns      1.852V     1.931V     1.756V
[Falling Waveform]
R_fixture = 50.000
V_fixture = 0.000
V_fixture_min = 0.000
V_fixture_max = 0.000
|  time   V(typ)   V(min)   V(max)
0s        690.2mV    515.7mV    902.9mV
380ps     689.9mV    515.4mV    901.3mV
432ps     690.5mV    515.4mV    749.5mV
481ps     677.9mV    515.2mV    457.8mV
574ps     406.4mV    507.3mV    124.7mV
626ps     201.5mV    441.1mV    69.74mV
695ps     91.47mV    285.4mV    34.66mV
806ps     31.7mV     84.42mV    12.22mV
1.016ns   5.217mV    14.22mV    1.921mV
50ns      49.18uV    -16.64uV   14.36uV
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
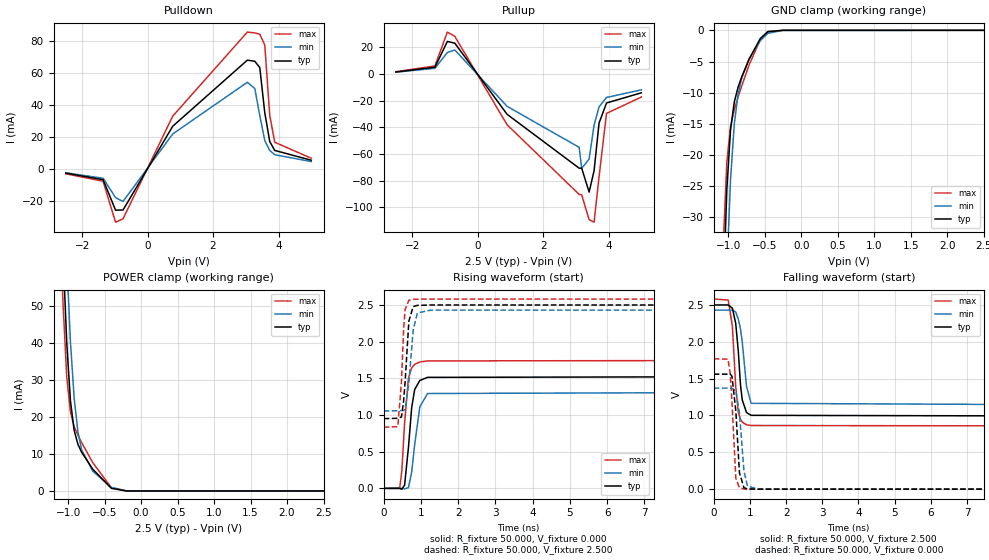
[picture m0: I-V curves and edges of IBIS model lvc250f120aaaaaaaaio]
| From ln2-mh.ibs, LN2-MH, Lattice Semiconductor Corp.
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|   Model lvc250f120aaaaaaaaio
[Model] lvc250f120aaaaaaaaio
Model_type I/O
Polarity   Non-Inverting
Enable   Active-Low
Vinl =  0.700V
Vinh =  1.700V
Vmeas =  1.250V
Cref =  0.0F
Rref =  1.000M
Vref =  0.0V
C_comp   2.000pF   1.500pF   2.500pF
[Temperature Range]   25.000   0.125k   -40.000
[Voltage Range]   2.500V   2.430V   2.580V
[C Comp Corner]
C_comp   2.000pF   1.500pF   2.500pF
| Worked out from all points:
|   slope of the pulldown table from 0 to 0.375 V, typ, clamps not added: 26 ohm
|   slope of the pullup table from 0 to 0.375 V, typ, clamps not added: 25.9 ohm
|   GND clamp passes 1 mA (typ) near -0.54 V on its own axis
|   POWER clamp passes 1 mA (typ) near -0.43 V on its own axis
|   rising waveform, R_fixture 50.000, V_fixture 0.000: 20-80 % time 164ps typ, 199ps min, 137ps max; typ from 0 V to 1.56 V
|   rising waveform, R_fixture 50.000, V_fixture 2.500: 20-80 % time 112ps typ, 135ps min, 93ps max; typ from 0.951 V to 2.5 V
|   falling waveform, R_fixture 50.000, V_fixture 2.500: 20-80 % time 150ps typ, 181ps min, 128ps max; typ from 2.5 V to 0.951 V
|   falling waveform, R_fixture 50.000, V_fixture 0.000: 20-80 % time 112ps typ, 132ps min, 99.4ps max; typ from 1.56 V to 0 V
[Pulldown]
|Voltage   I(typ)   I(min)   I(max)
-2.5V     -2.714mA   -2.454mA   -3.099mA
-1.36V    -6.743mA   -5.871mA   -7.753mA
-980mV    -25.82mA   -17.98mA   -33.34mA
-752mV    -25.74mA   -20.4mA    -31.26mA
768mV     26.64mA    21.81mA    32.95mA
3.048V    67.96mA    54.13mA    85.49mA
3.276V    67.23mA    50.2mA     84.98mA
3.428V    63.31mA    33.27mA    84.18mA
3.58V     35.15mA    17.71mA    77.43mA
3.732V    17.14mA    11.54mA    33.56mA
3.884V    11.52mA    8.821mA    16.63mA
5V        5.406mA    4.566mA    6.645mA
[Pullup]
|Voltage   I(typ)   I(min)   I(max)
-2.5V     1.552mA    1.436mA    1.807mA
-1.308V   5.16mA     4.342mA    6.104mA
-928mV    24.53mA    16.26mA    31.55mA
-700mV    23.22mA    18.1mA     28.33mA
896mV     -30.21mA   -24.22mA   -38.06mA
3.1V      -70.73mA   -55.07mA   -90.44mA
3.176V    -70.68mA   -70.92mA   -90.68mA
3.404V    -88.65mA   -63.77mA   -109.4mA
3.556V    -72.54mA   -38.31mA   -111.3mA
3.708V    -36.71mA   -24.6mA    -77mA
3.936V    -21.71mA   -17.58mA   -29.53mA
5V        -14.08mA   -11.84mA   -17.25mA
[GND_clamp]
|Voltage   I(typ)   I(min)   I(max)
-2.5V     -1.176A    -1.175A    -1.18A
-1.072V   -43.12mA   -59.87mA   -34.84mA
-1.021V   -25.46mA   -38.72mA   -21.1mA
-970mV    -15.9mA    -23.88mA   -15.42mA
-919mV    -11.5mA    -15.05mA   -12.74mA
-868mV    -9.155mA   -10.31mA   -10.74mA
-817mV    -7.451mA   -7.678mA   -8.924mA
-715mV    -4.588mA   -4.605mA   -5.525mA
-562mV    -1.31mA    -1.648mA   -1.483mA
-460mV    -221.2uA   -492.9uA   -183.3uA
-256mV    -336.9nA   -5.429uA   -53.89nA
2.5V      0A         0A         0A
[POWER_clamp]
|Voltage   I(typ)   I(min)   I(max)
-2.498V   1.294A     1.303A     1.292A
-1.121V   95.13mA    121.6mA    80.05mA
-1.07V    64.31mA    89.69mA    50.73mA
-1.019V   40mA       62.1mA     30.81mA
-968mV    24.27mA    40.19mA    21.27mA
-917mV    16.31mA    24.99mA    17.34mA
-866mV    12.6mA     15.97mA    15.03mA
-815mV    10.45mA    11.12mA    13.06mA
-662mV    5.856mA    5.328mA    7.611mA
-407mV    698.4uA    949.4uA    879.7uA
-203mV    1.851uA    18.03uA    575.7nA
2.5V      0A         0A         0A
[Ramp]
| variable   typ   min   max
dV/dt_r   0.959/0.164n   0.842/0.199n   1.085/0.137n
dV/dt_f   0.951/0.150n   0.845/0.182n   1.071/0.128n
R_load = 50.000
[Rising Waveform]
R_fixture = 50.000
V_fixture = 0.000
V_fixture_min = 0.000
V_fixture_max = 0.000
|  time   V(typ)   V(min)   V(max)
0s        28.32uV    32.51uV    26.09uV
431ps     15.6uV     -285.4uV   7.534mV
488ps     -10.59mV   -51.58uV   238.8mV
562ps     44.13mV    -5.91mV    887.8mV
666ps     560.2mV    10.51mV    1.503V
752ps     1.1V       221.5mV    1.643V
833ps     1.347V     596.9mV    1.69V
971ps     1.471V     1.112V     1.723V
1.18ns    1.513V     1.293V     1.737V
50ns      1.561V     1.371V     1.77V
[Rising Waveform]
R_fixture = 50.000
V_fixture = 2.500
V_fixture_min = 2.430
V_fixture_max = 2.580
|  time   V(typ)   V(min)   V(max)
0s        950.8mV    1.055V     833.1mV
381ps     955mV      1.058V     842.3mV
478ps     972.8mV    1.06V      1.453V
537ps     1.194V     1.06V      2.177V
577ps     1.457V     1.083V     2.439V
677ps     2.28V      1.434V     2.563V
792ps     2.477V     2.154V     2.576V
906ps     2.494V     2.391V     2.578V
1.269ns   2.499V     2.429V     2.58V
50ns      2.5V       2.43V      2.58V
[Falling Waveform]
R_fixture = 50.000
V_fixture = 2.500
V_fixture_min = 2.430
V_fixture_max = 2.580
|  time   V(typ)   V(min)   V(max)
0s        2.5V       2.43V      2.58V
399ps     2.5V       2.43V      2.567V
514ps     2.456V     2.43V      2.214V
606ps     2.252V     2.405V     1.397V
677ps     1.877V     2.309V     1.047V
739ps     1.415V     2.171V     944.7mV
787ps     1.212V     1.999V     910.1mV
904ps     1.041V     1.398V     874.6mV
1.033ns   1.002V     1.165V     863.9mV
50ns      950.8mV    1.055V     833.1mV
[Falling Waveform]
R_fixture = 50.000
V_fixture = 0.000
V_fixture_min = 0.000
V_fixture_max = 0.000
|  time   V(typ)   V(min)   V(max)
0s        1.561V     1.371V     1.77V
394ps     1.561V     1.371V     1.764V
456ps     1.564V     1.371V     1.56V
504ps     1.53V      1.371V     1.174V
610ps     1.059V     1.333V     147.3mV
710ps     221.4mV    1.032V     18.51mV
834ps     19.5mV     249.2mV    2.534mV
933ps     4.127mV    40.12mV    707.2uV
1.234ns   207.9uV    756.9uV    126.6uV
50ns      28.32uV    32.51uV    26.09uV
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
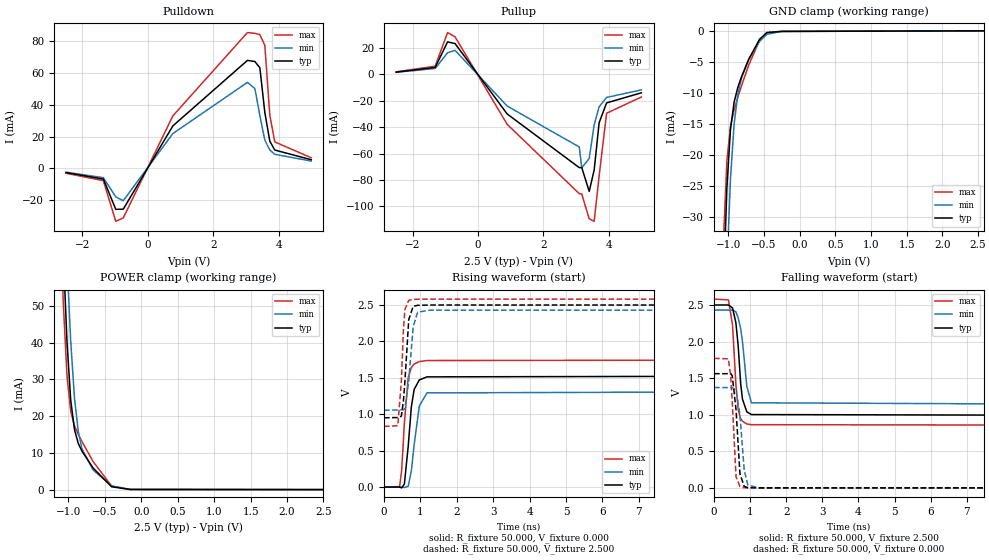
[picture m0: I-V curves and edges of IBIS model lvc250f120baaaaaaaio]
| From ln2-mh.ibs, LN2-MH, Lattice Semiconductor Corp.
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|   Model lvc250f120baaaaaaaio
[Model] lvc250f120baaaaaaaio
Model_type I/O
Polarity   Non-Inverting
Enable   Active-Low
Vinl =  0.700V
Vinh =  1.700V
Vmeas =  1.250V
Cref =  0.0F
Rref =  1.000M
Vref =  0.0V
C_comp   2.000pF   1.500pF   2.500pF
[Temperature Range]   25.000   0.125k   -40.000
[Voltage Range]   2.500V   2.430V   2.580V
[C Comp Corner]
C_comp   2.000pF   1.500pF   2.500pF
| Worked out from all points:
|   slope of the pulldown table from 0 to 0.375 V, typ, clamps not added: 26 ohm
|   slope of the pullup table from 0 to 0.375 V, typ, clamps not added: 26 ohm
|   GND clamp passes 1 mA (typ) near -0.53 V on its own axis
|   POWER clamp passes 1 mA (typ) near -0.42 V on its own axis
|   rising waveform, R_fixture 50.000, V_fixture 0.000: 20-80 % time 164ps typ, 199ps min, 137ps max; typ from 0 V to 1.56 V
|   rising waveform, R_fixture 50.000, V_fixture 2.500: 20-80 % time 112ps typ, 135ps min, 93ps max; typ from 0.951 V to 2.5 V
|   falling waveform, R_fixture 50.000, V_fixture 2.500: 20-80 % time 150ps typ, 181ps min, 128ps max; typ from 2.5 V to 0.951 V
|   falling waveform, R_fixture 50.000, V_fixture 0.000: 20-80 % time 112ps typ, 132ps min, 99.4ps max; typ from 1.56 V to 0 V
[Pulldown]
|Voltage   I(typ)   I(min)   I(max)
-2.5V     -2.713mA   -2.452mA   -3.097mA
-1.36V    -6.741mA   -5.868mA   -7.75mA
-980mV    -25.81mA   -17.97mA   -33.33mA
-752mV    -25.71mA   -20.38mA   -31.24mA
768mV     26.73mA    21.9mA     33.04mA
3.048V    67.91mA    54.09mA    85.42mA
3.276V    67.19mA    50.17mA    84.93mA
3.428V    63.28mA    33.25mA    84.14mA
3.58V     35.13mA    17.7mA     77.39mA
3.732V    17.13mA    11.54mA    33.54mA
3.884V    11.51mA    8.816mA    16.62mA
5V        5.403mA    4.564mA    6.641mA
[Pullup]
|Voltage   I(typ)   I(min)   I(max)
-2.5V     1.549mA    1.434mA    1.804mA
-1.308V   5.154mA    4.335mA    6.097mA
-928mV    24.49mA    16.24mA    31.51mA
-700mV    23.18mA    18.06mA    28.28mA
896mV     -30.11mA   -24.12mA   -37.97mA
3.1V      -70.69mA   -55.04mA   -90.38mA
3.176V    -70.65mA   -70.9mA    -90.64mA
3.404V    -88.64mA   -63.76mA   -109.4mA
3.556V    -72.54mA   -38.3mA    -111.3mA
3.708V    -36.71mA   -24.6mA    -77mA
3.936V    -21.7mA    -17.58mA   -29.53mA
5V        -14.08mA   -11.84mA   -17.25mA
[GND_clamp]
|Voltage   I(typ)   I(min)   I(max)
-2.5V     -1.176A    -1.175A    -1.18A
-1.072V   -43.12mA   -59.88mA   -34.84mA
-1.021V   -25.47mA   -38.73mA   -21.11mA
-970mV    -15.91mA   -23.89mA   -15.44mA
-919mV    -11.52mA   -15.06mA   -12.75mA
-868mV    -9.172mA   -10.33mA   -10.76mA
-817mV    -7.47mA    -7.698mA   -8.941mA
-715mV    -4.614mA   -4.632mA   -5.549mA
-562mV    -1.356mA   -1.692mA   -1.528mA
-460mV    -296.7uA   -557.9uA   -261.8uA
-256mV    -93.15uA   -97.62uA   -93.76uA
2.58V     0A         0A         0A
[POWER_clamp]
|Voltage   I(typ)   I(min)   I(max)
-2.498V   1.294A     1.303A     1.292A
-1.121V   95.14mA    121.6mA    80.07mA
-1.07V    64.33mA    89.71mA    50.75mA
-1.019V   40.02mA    62.12mA    30.84mA
-968mV    24.3mA     40.21mA    21.31mA
-917mV    16.34mA    25.01mA    17.39mA
-866mV    12.64mA    16mA       15.07mA
-815mV    10.49mA    11.15mA    13.11mA
-662mV    5.902mA    5.367mA    7.663mA
-407mV    768.2uA    1.002mA    960.5uA
-152mV    40.9uA     39.04uA    48.9uA
2.5V      0A         0A         0A
[Ramp]
| variable   typ   min   max
dV/dt_r   0.959/0.164n   0.842/0.199n   1.085/0.137n
dV/dt_f   0.951/0.150n   0.845/0.182n   1.071/0.128n
R_load = 50.000
[Rising Waveform]
R_fixture = 50.000
V_fixture = 0.000
V_fixture_min = 0.000
V_fixture_max = 0.000
|  time   V(typ)   V(min)   V(max)
0s        29.03uV    32.39uV    24.96uV
431ps     30.74uV    -285.5uV   7.533mV
488ps     -10.51mV   -51.7uV    238.8mV
561ps     40.93mV    -5.735mV   878.5mV
666ps     557.7mV    10.51mV    1.503V
752ps     1.099V     221.5mV    1.643V
830ps     1.341V     582mV      1.689V
971ps     1.471V     1.112V     1.723V
1.181ns   1.513V     1.293V     1.737V
50ns      1.561V     1.371V     1.77V
[Rising Waveform]
R_fixture = 50.000
V_fixture = 2.500
V_fixture_min = 2.430
V_fixture_max = 2.580
|  time   V(typ)   V(min)   V(max)
0s        950.8mV    1.055V     833.1mV
381ps     955mV      1.058V     842.2mV
478ps     972.8mV    1.06V      1.452V
537ps     1.194V     1.06V      2.176V
577ps     1.457V     1.083V     2.439V
681ps     2.299V     1.458V     2.564V
803ps     2.481V     2.202V     2.576V
926ps     2.495V     2.401V     2.579V
1.269ns   2.499V     2.429V     2.58V
50ns      2.5V       2.43V      2.58V
[Falling Waveform]
R_fixture = 50.000
V_fixture = 2.500
V_fixture_min = 2.430
V_fixture_max = 2.580
|  time   V(typ)   V(min)   V(max)
0s        2.5V       2.43V      2.58V
397ps     2.5V       2.43V      2.57V
512ps     2.459V     2.43V      2.224V
604ps     2.258V     2.408V     1.413V
669ps     1.935V     2.322V     1.068V
738ps     1.419V     2.174V     945.6mV
787ps     1.212V     2V         910mV
907ps     1.039V     1.388V     874mV
1.035ns   1.002V     1.163V     863.6mV
50ns      950.8mV    1.055V     833.1mV
[Falling Waveform]
R_fixture = 50.000
V_fixture = 0.000
V_fixture_min = 0.000
V_fixture_max = 0.000
|  time   V(typ)   V(min)   V(max)
0s        1.561V     1.371V     1.77V
394ps     1.561V     1.371V     1.764V
457ps     1.564V     1.371V     1.553V
504ps     1.531V     1.371V     1.173V
609ps     1.067V     1.335V     150.5mV
716ps     194.3mV    1.001V     16.56mV
835ps     19.22mV    245.4mV    2.49mV
934ps     4.079mV    39.51mV    698.2uV
1.234ns   208.9uV    757.8uV    125.5uV
50ns      29.03uV    32.39uV    24.96uV
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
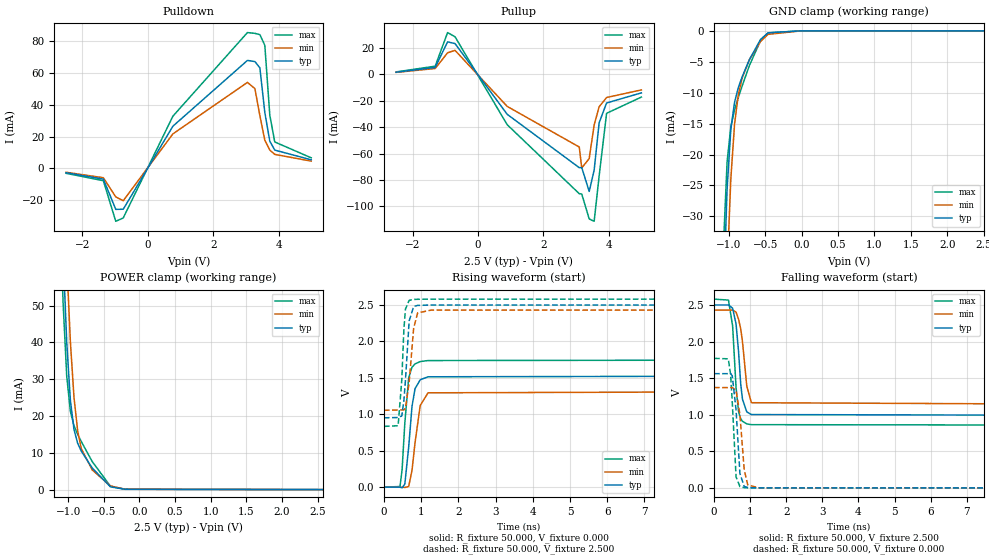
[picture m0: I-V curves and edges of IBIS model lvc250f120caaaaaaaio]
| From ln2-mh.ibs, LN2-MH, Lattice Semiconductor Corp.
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|   Model lvc250f120caaaaaaaio
[Model] lvc250f120caaaaaaaio
Model_type I/O
Polarity   Non-Inverting
Enable   Active-Low
Vinl =  0.700V
Vinh =  1.700V
Vmeas =  1.250V
Cref =  0.0F
Rref =  1.000M
Vref =  0.0V
C_comp   2.000pF   1.500pF   2.500pF
[Temperature Range]   25.000   0.125k   -40.000
[Voltage Range]   2.500V   2.430V   2.580V
[C Comp Corner]
C_comp   2.000pF   1.500pF   2.500pF
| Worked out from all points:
|   slope of the pulldown table from 0 to 0.375 V, typ, clamps not added: 26.1 ohm
|   slope of the pullup table from 0 to 0.375 V, typ, clamps not added: 25.9 ohm
|   GND clamp passes 1 mA (typ) near -0.53 V on its own axis
|   POWER clamp passes 1 mA (typ) near -0.43 V on its own axis
|   rising waveform, R_fixture 50.000, V_fixture 0.000: 20-80 % time 164ps typ, 199ps min, 137ps max; typ from 0 V to 1.56 V
|   rising waveform, R_fixture 50.000, V_fixture 2.500: 20-80 % time 112ps typ, 135ps min, 93.1ps max; typ from 0.951 V to 2.5 V
|   falling waveform, R_fixture 50.000, V_fixture 2.500: 20-80 % time 150ps typ, 181ps min, 128ps max; typ from 2.5 V to 0.951 V
|   falling waveform, R_fixture 50.000, V_fixture 0.000: 20-80 % time 112ps typ, 132ps min, 99.4ps max; typ from 1.56 V to 0 V
[Pulldown]
|Voltage   I(typ)   I(min)   I(max)
-2.5V     -2.708mA   -2.448mA   -3.091mA
-1.36V    -6.732mA   -5.861mA   -7.74mA
-980mV    -25.78mA   -17.94mA   -33.28mA
-752mV    -25.68mA   -20.35mA   -31.19mA
768mV     26.55mA    21.72mA    32.86mA
3.048V    67.93mA    54.1mA     85.45mA
3.276V    67.21mA    50.18mA    84.96mA
3.428V    63.3mA     33.26mA    84.17mA
3.58V     35.14mA    17.71mA    77.42mA
3.732V    17.13mA    11.54mA    33.55mA
3.884V    11.51mA    8.819mA    16.63mA
5V        5.405mA    4.565mA    6.644mA
[Pullup]
|Voltage   I(typ)   I(min)   I(max)
-2.5V     1.551mA    1.435mA    1.806mA
-1.308V   5.158mA    4.339mA    6.103mA
-928mV    24.52mA    16.25mA    31.54mA
-700mV    23.2mA     18.08mA    28.32mA
896mV     -30.3mA    -24.31mA   -38.15mA
3.1V      -70.65mA   -55.01mA   -90.32mA
3.176V    -70.61mA   -70.87mA   -90.58mA
3.404V    -88.6mA    -63.74mA   -109.4mA
3.556V    -72.51mA   -38.29mA   -111.2mA
3.708V    -36.7mA    -24.59mA   -76.98mA
3.936V    -21.7mA    -17.57mA   -29.52mA
5V        -14.08mA   -11.83mA   -17.25mA
[GND_clamp]
|Voltage   I(typ)   I(min)   I(max)
-2.5V     -1.176A    -1.175A    -1.18A
-1.072V   -43.15mA   -59.89mA   -34.87mA
-1.021V   -25.5mA    -38.75mA   -21.15mA
-970mV    -15.94mA   -23.91mA   -15.48mA
-919mV    -11.55mA   -15.09mA   -12.8mA
-868mV    -9.208mA   -10.36mA   -10.81mA
-817mV    -7.507mA   -7.725mA   -8.99mA
-715mV    -4.652mA   -4.658mA   -5.6mA
-562mV    -1.396mA   -1.715mA   -1.585mA
-460mV    -331.3uA   -573.9uA   -320.1uA
-1mV      -317.6nA   -575.7nA   -335.3nA
2.5V      0A         0A         0A
[POWER_clamp]
|Voltage   I(typ)   I(min)   I(max)
-2.498V   1.294A     1.303A     1.292A
-1.121V   95.13mA    121.6mA    80.05mA
-1.07V    64.32mA    89.7mA     50.73mA
-1.019V   40.01mA    62.11mA    30.82mA
-968mV    24.28mA    40.2mA     21.28mA
-917mV    16.32mA    25mA       17.36mA
-866mV    12.61mA    15.98mA    15.04mA
-815mV    10.46mA    11.14mA    13.07mA
-662mV    5.878mA    5.353mA    7.63mA
-407mV    756.4uA    1.004mA    934.2uA
-203mV    93.32uA    107.9uA    92.71uA
2.58V     0A         0A         0A
[Ramp]
| variable   typ   min   max
dV/dt_r   0.959/0.164n   0.842/0.199n   1.085/0.137n
dV/dt_f   0.951/0.150n   0.845/0.182n   1.071/0.128n
R_load = 50.000
[Rising Waveform]
R_fixture = 50.000
V_fixture = 0.000
V_fixture_min = 0.000
V_fixture_max = 0.000
|  time   V(typ)   V(min)   V(max)
0s        32.67uV    -14.14uV   8.614uV
431ps     34.38uV    -332.1uV   7.549mV
488ps     -10.51mV   -98.17uV   239mV
561ps     40.94mV    -5.809mV   878.6mV
665ps     550.8mV    9.306mV    1.5V
754ps     1.108V     228.9mV    1.645V
836ps     1.352V     611.7mV    1.691V
975ps     1.473V     1.12V      1.723V
1.185ns   1.514V     1.294V     1.737V
50ns      1.561V     1.371V     1.77V
[Rising Waveform]
R_fixture = 50.000
V_fixture = 2.500
V_fixture_min = 2.430
V_fixture_max = 2.580
|  time   V(typ)   V(min)   V(max)
0s        950.8mV    1.055V     833.1mV
381ps     955mV      1.058V     842.2mV
480ps     976.9mV    1.06V      1.475V
536ps     1.189V     1.06V      2.166V
578ps     1.465V     1.085V     2.443V
677ps     2.28V      1.434V     2.563V
798ps     2.479V     2.181V     2.576V
906ps     2.494V     2.391V     2.578V
1.269ns   2.499V     2.429V     2.58V
50ns      2.5V       2.43V      2.58V
[Falling Waveform]
R_fixture = 50.000
V_fixture = 2.500
V_fixture_min = 2.430
V_fixture_max = 2.580
|  time   V(typ)   V(min)   V(max)
0s        2.5V       2.43V      2.58V
399ps     2.5V       2.43V      2.567V
514ps     2.456V     2.43V      2.214V
609ps     2.24V      2.402V     1.372V
678ps     1.868V     2.307V     1.044V
738ps     1.419V     2.174V     945.7mV
787ps     1.212V     1.999V     910.1mV
906ps     1.039V     1.391V     874.3mV
1.034ns   1.002V     1.164V     863.9mV
50ns      950.8mV    1.055V     833.1mV
[Falling Waveform]
R_fixture = 50.000
V_fixture = 0.000
V_fixture_min = 0.000
V_fixture_max = 0.000
|  time   V(typ)   V(min)   V(max)
0s        1.561V     1.371V     1.77V
394ps     1.561V     1.371V     1.764V
457ps     1.564V     1.371V     1.553V
504ps     1.531V     1.371V     1.173V
609ps     1.067V     1.335V     150.5mV
716ps     194.3mV    1.001V     16.55mV
835ps     19.23mV    245.3mV    2.474mV
934ps     4.082mV    39.47mV    681.9uV
1.234ns   212.5uV    711.3uV    109.2uV
50ns      32.67uV    -14.14uV   8.614uV
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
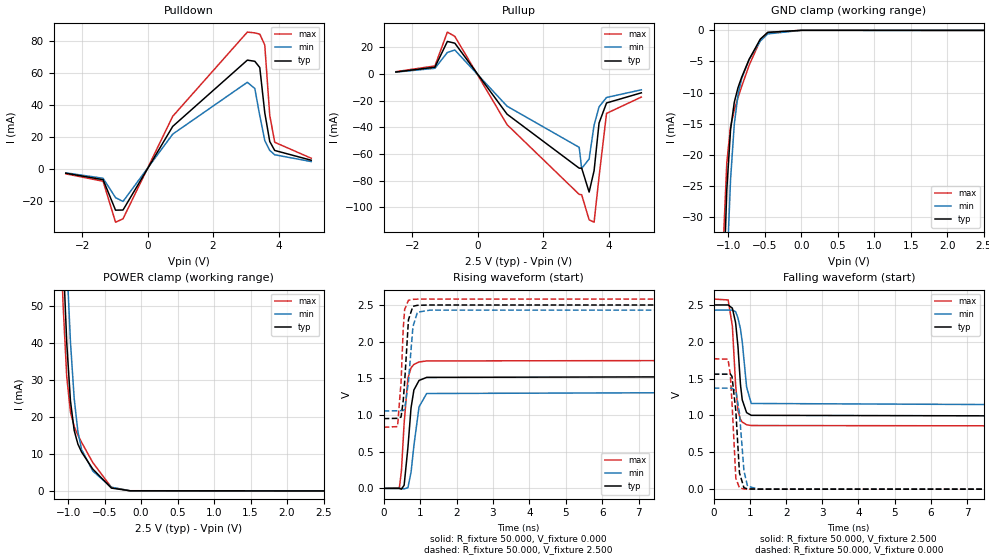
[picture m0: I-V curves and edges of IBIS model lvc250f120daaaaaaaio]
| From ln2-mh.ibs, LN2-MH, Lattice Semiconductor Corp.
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|   Model lvc250f120daaaaaaaio
[Model] lvc250f120daaaaaaaio
Model_type I/O
Polarity   Non-Inverting
Enable   Active-Low
Vinl =  0.700V
Vinh =  1.700V
Vmeas =  1.250V
Cref =  0.0F
Rref =  1.000M
Vref =  0.0V
C_comp   2.000pF   1.500pF   2.500pF
[Temperature Range]   25.000   0.125k   -40.000
[Voltage Range]   2.500V   2.430V   2.580V
[C Comp Corner]
C_comp   2.000pF   1.500pF   2.500pF
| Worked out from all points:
|   slope of the pulldown table from 0 to 0.375 V, typ, clamps not added: 26.1 ohm
|   slope of the pullup table from 0 to 0.375 V, typ, clamps not added: 26 ohm
|   GND clamp passes 1 mA (typ) near -0.53 V on its own axis
|   POWER clamp passes 1 mA (typ) near -0.42 V on its own axis
|   rising waveform, R_fixture 50.000, V_fixture 0.000: 20-80 % time 164ps typ, 199ps min, 137ps max; typ from 0 V to 1.56 V
|   rising waveform, R_fixture 50.000, V_fixture 2.500: 20-80 % time 112ps typ, 135ps min, 93ps max; typ from 0.951 V to 2.5 V
|   falling waveform, R_fixture 50.000, V_fixture 2.500: 20-80 % time 150ps typ, 181ps min, 128ps max; typ from 2.5 V to 0.951 V
|   falling waveform, R_fixture 50.000, V_fixture 0.000: 20-80 % time 112ps typ, 132ps min, 99.4ps max; typ from 1.56 V to 0 V
[Pulldown]
|Voltage   I(typ)   I(min)   I(max)
-2.5V     -2.708mA   -2.448mA   -3.091mA
-1.36V    -6.732mA   -5.861mA   -7.74mA
-980mV    -25.78mA   -17.94mA   -33.28mA
-752mV    -25.68mA   -20.35mA   -31.19mA
768mV     26.55mA    21.72mA    32.86mA
3.048V    67.91mA    54.09mA    85.42mA
3.276V    67.19mA    50.17mA    84.93mA
3.428V    63.28mA    33.25mA    84.14mA
3.58V     35.13mA    17.7mA     77.39mA
3.732V    17.13mA    11.54mA    33.54mA
3.884V    11.51mA    8.816mA    16.62mA
5V        5.403mA    4.564mA    6.641mA
[Pullup]
|Voltage   I(typ)   I(min)   I(max)
-2.5V     1.549mA    1.434mA    1.804mA
-1.308V   5.154mA    4.335mA    6.097mA
-928mV    24.49mA    16.24mA    31.51mA
-700mV    23.18mA    18.06mA    28.28mA
896mV     -30.11mA   -24.12mA   -37.97mA
3.1V      -70.65mA   -55.01mA   -90.32mA
3.176V    -70.61mA   -70.87mA   -90.58mA
3.404V    -88.6mA    -63.74mA   -109.4mA
3.556V    -72.51mA   -38.29mA   -111.2mA
3.708V    -36.7mA    -24.59mA   -76.98mA
3.936V    -21.7mA    -17.57mA   -29.52mA
5V        -14.08mA   -11.83mA   -17.25mA
[GND_clamp]
|Voltage   I(typ)   I(min)   I(max)
-2.5V     -1.176A    -1.175A    -1.18A
-1.072V   -43.15mA   -59.89mA   -34.87mA
-1.021V   -25.5mA    -38.75mA   -21.15mA
-970mV    -15.94mA   -23.91mA   -15.48mA
-919mV    -11.55mA   -15.09mA   -12.8mA
-868mV    -9.208mA   -10.36mA   -10.81mA
-817mV    -7.507mA   -7.725mA   -8.99mA
-715mV    -4.652mA   -4.658mA   -5.6mA
-562mV    -1.396mA   -1.715mA   -1.585mA
-460mV    -331.3uA   -573.9uA   -320.1uA
-1mV      -317.6nA   -575.7nA   -335.3nA
2.5V      19.47nA    0A         -24.11uA
[POWER_clamp]
|Voltage   I(typ)   I(min)   I(max)
-2.498V   1.294A     1.303A     1.292A
-1.121V   95.14mA    121.6mA    80.07mA
-1.07V    64.33mA    89.71mA    50.75mA
-1.019V   40.02mA    62.12mA    30.84mA
-968mV    24.3mA     40.21mA    21.31mA
-917mV    16.34mA    25.01mA    17.39mA
-866mV    12.64mA    16mA       15.07mA
-815mV    10.49mA    11.15mA    13.11mA
-662mV    5.902mA    5.367mA    7.663mA
-407mV    768.2uA    1.002mA    960.5uA
-152mV    40.9uA     39.04uA    48.9uA
2.5V      0A         0A         24.96uA
[Ramp]
| variable   typ   min   max
dV/dt_r   0.959/0.164n   0.842/0.199n   1.085/0.137n
dV/dt_f   0.951/0.150n   0.845/0.182n   1.071/0.128n
R_load = 50.000
[Rising Waveform]
R_fixture = 50.000
V_fixture = 0.000
V_fixture_min = 0.000
V_fixture_max = 0.000
|  time   V(typ)   V(min)   V(max)
0s        32.67uV    -14.14uV   8.614uV
431ps     34.38uV    -332.1uV   7.516mV
488ps     -10.51mV   -99.68uV   238.8mV
562ps     43.15mV    -5.929mV   887.8mV
666ps     557.7mV    10.2mV     1.503V
752ps     1.099V     220.7mV    1.643V
830ps     1.341V     581.1mV    1.689V
971ps     1.471V     1.111V     1.723V
1.181ns   1.513V     1.293V     1.737V
50ns      1.561V     1.371V     1.77V
[Rising Waveform]
R_fixture = 50.000
V_fixture = 2.500
V_fixture_min = 2.430
V_fixture_max = 2.580
|  time   V(typ)   V(min)   V(max)
0s        950.8mV    1.055V     833.1mV
381ps     955mV      1.058V     842.2mV
478ps     972.8mV    1.06V      1.452V
537ps     1.194V     1.06V      2.176V
577ps     1.457V     1.083V     2.439V
681ps     2.299V     1.458V     2.564V
803ps     2.481V     2.202V     2.576V
926ps     2.495V     2.401V     2.579V
1.27ns    2.499V     2.429V     2.58V
50ns      2.5V       2.43V      2.58V
[Falling Waveform]
R_fixture = 50.000
V_fixture = 2.500
V_fixture_min = 2.430
V_fixture_max = 2.580
|  time   V(typ)   V(min)   V(max)
0s        2.5V       2.43V      2.58V
398ps     2.5V       2.43V      2.568V
514ps     2.456V     2.43V      2.213V
604ps     2.258V     2.408V     1.412V
669ps     1.935V     2.322V     1.068V
738ps     1.419V     2.174V     945.5mV
787ps     1.212V     2V         910mV
907ps     1.039V     1.388V     874.1mV
1.035ns   1.002V     1.163V     863.8mV
50ns      950.8mV    1.055V     833.1mV
[Falling Waveform]
R_fixture = 50.000
V_fixture = 0.000
V_fixture_min = 0.000
V_fixture_max = 0.000
|  time   V(typ)   V(min)   V(max)
0s        1.561V     1.371V     1.77V
394ps     1.561V     1.371V     1.764V
456ps     1.564V     1.371V     1.56V
504ps     1.53V      1.371V     1.174V
610ps     1.059V     1.333V     147.3mV
710ps     221.4mV    1.032V     18.5mV
834ps     19.5mV     249.2mV    2.516mV
933ps     4.132mV    40.07mV    689.7uV
1.234ns   212.3uV    710.2uV    109.2uV
50ns      32.67uV    -14.14uV   8.614uV
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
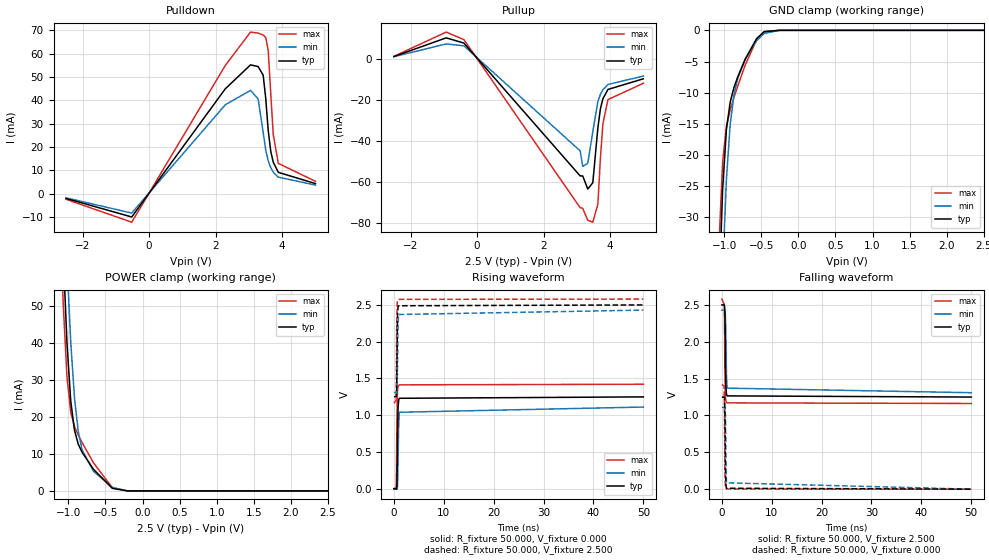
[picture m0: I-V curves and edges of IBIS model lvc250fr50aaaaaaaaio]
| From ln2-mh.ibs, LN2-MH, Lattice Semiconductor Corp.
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|   Model lvc250fr50aaaaaaaaio
[Model] lvc250fr50aaaaaaaaio
Model_type I/O
Polarity   Non-Inverting
Enable   Active-Low
Vinl =  0.700V
Vinh =  1.700V
Vmeas =  1.250V
Cref =  0.0F
Rref =  1.000M
Vref =  0.0V
C_comp   2.000pF   1.500pF   2.500pF
[Temperature Range]   25.000   0.125k   -40.000
[Voltage Range]   2.500V   2.430V   2.580V
[C Comp Corner]
C_comp   2.000pF   1.500pF   2.500pF
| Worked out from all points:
|   slope of the pulldown table from 0 to 0.375 V, typ, clamps not added: 49.6 ohm
|   slope of the pullup table from 0 to 0.375 V, typ, clamps not added: 49.7 ohm
|   GND clamp passes 1 mA (typ) near -0.54 V on its own axis
|   POWER clamp passes 1 mA (typ) near -0.43 V on its own axis
|   rising waveform, R_fixture 50.000, V_fixture 0.000: 20-80 % time 140ps typ, 179ps min, 116ps max; typ from 0 V to 1.25 V
|   rising waveform, R_fixture 50.000, V_fixture 2.500: 20-80 % time 108ps typ, 132ps min, 87.8ps max; typ from 1.25 V to 2.5 V
|   falling waveform, R_fixture 50.000, V_fixture 2.500: 20-80 % time 119ps typ, 149ps min, 102ps max; typ from 2.5 V to 1.25 V
|   falling waveform, R_fixture 50.000, V_fixture 0.000: 20-80 % time 102ps typ, 118ps min, 90.9ps max; typ from 1.25 V to 0 V
[Pulldown]
|Voltage   I(typ)   I(min)   I(max)
-2.5V     -2.071mA   -1.824mA   -2.44mA
-524mV    -10.03mA   -8.352mA   -12.26mA
2.288V    44.85mA    38.02mA    54.86mA
3.048V    55.14mA    44.2mA     69.18mA
3.276V    54.42mA    40.57mA    68.75mA
3.428V    50.74mA    26.29mA    67.92mA
3.504V    40.95mA    18.79mA    66.9mA
3.58V     27.12mA    14mA       61.4mA
3.656V    18.13mA    11.1mA     42.88mA
3.732V    13.4mA     9.166mA    25.25mA
3.884V    9.092mA    7.018mA    12.92mA
5V        4.273mA    3.633mA    5.257mA
[Pullup]
|Voltage   I(typ)   I(min)   I(max)
-2.5V     1.035mA    953.2uA    1.128mA
-928mV    10.12mA    7.17mA     12.92mA
-396mV    7.585mA    6.248mA    9.268mA
3.1V      -56.99mA   -44.79mA   -72.44mA
3.176V    -56.96mA   -52.34mA   -72.71mA
3.328V    -63.36mA   -50.85mA   -78.5mA
3.48V     -60.29mA   -35.47mA   -79.46mA
3.632V    -33.66mA   -20.83mA   -70.7mA
3.708V    -24.42mA   -17.34mA   -48.55mA
3.784V    -19.47mA   -15.12mA   -31.57mA
3.936V    -14.95mA   -12.53mA   -19.89mA
5V        -9.786mA   -8.448mA   -11.95mA
[GND_clamp]
|Voltage   I(typ)   I(min)   I(max)
-2.5V     -1.176A    -1.175A    -1.18A
-1.072V   -43.12mA   -59.87mA   -34.84mA
-1.021V   -25.46mA   -38.72mA   -21.1mA
-970mV    -15.9mA    -23.88mA   -15.42mA
-919mV    -11.5mA    -15.05mA   -12.74mA
-868mV    -9.155mA   -10.31mA   -10.74mA
-817mV    -7.451mA   -7.678mA   -8.924mA
-715mV    -4.588mA   -4.605mA   -5.525mA
-562mV    -1.31mA    -1.648mA   -1.483mA
-460mV    -221.2uA   -492.9uA   -183.3uA
-256mV    -336.9nA   -5.429uA   -53.89nA
2.5V      0A         0A         0A
[POWER_clamp]
|Voltage   I(typ)   I(min)   I(max)
-2.498V   1.294A     1.303A     1.292A
-1.121V   95.13mA    121.6mA    80.05mA
-1.07V    64.31mA    89.69mA    50.73mA
-1.019V   40mA       62.1mA     30.81mA
-968mV    24.27mA    40.19mA    21.27mA
-917mV    16.31mA    24.99mA    17.34mA
-866mV    12.6mA     15.97mA    15.03mA
-815mV    10.45mA    11.12mA    13.06mA
-662mV    5.856mA    5.328mA    7.611mA
-407mV    698.4uA    949.4uA    879.7uA
-203mV    1.851uA    18.03uA    575.7nA
2.5V      0A         0A         0A
[Ramp]
| variable   typ   min   max
dV/dt_r   0.765/0.141n   0.681/0.179n   0.870/0.117n
dV/dt_f   0.765/0.120n   0.687/0.151n   0.867/0.102n
R_load = 50.000
[Rising Waveform]
R_fixture = 50.000
V_fixture = 0.000
V_fixture_min = 0.000
V_fixture_max = 0.000
|  time   V(typ)   V(min)   V(max)
0s        3.011uV    6.324uV    2.098uV
463ps     -2.604mV   -232.2uV   15.59mV
510ps     -6.389mV   -39.04uV   218.3mV
598ps     48.76mV    -5.374mV   918.8mV
702ps     573.7mV    7.374mV    1.314V
768ps     927mV      147.8mV    1.373V
832ps     1.106V     399.8mV    1.392V
963ps     1.21V      878.9mV    1.407V
1.093ns   1.23V      1.04V      1.413V
50ns      1.249V     1.111V     1.421V
[Rising Waveform]
R_fixture = 50.000
V_fixture = 2.500
V_fixture_min = 2.430
V_fixture_max = 2.580
|  time   V(typ)   V(min)   V(max)
0s        1.25V      1.309V     1.163V
442ps     1.251V     1.31V      1.2V
477ps     1.249V     1.31V      1.4V
550ps     1.323V     1.309V     2.166V
632ps     1.873V     1.339V     2.488V
682ps     2.209V     1.488V     2.539V
733ps     2.374V     1.757V     2.56V
820ps     2.464V     2.194V     2.572V
920ps     2.489V     2.37V      2.576V
50ns      2.5V       2.43V      2.58V
[Falling Waveform]
R_fixture = 50.000
V_fixture = 2.500
V_fixture_min = 2.430
V_fixture_max = 2.580
|  time   V(typ)   V(min)   V(max)
0s        2.5V       2.43V      2.58V
480ps     2.502V     2.43V      2.509V
541ps     2.491V     2.431V     2.284V
612ps     2.396V     2.43V      1.634V
692ps     2.004V     2.389V     1.289V
749ps     1.609V     2.302V     1.223V
809ps     1.403V     2.091V     1.196V
924ps     1.292V     1.554V     1.177V
1.054ns   1.266V     1.371V     1.171V
50ns      1.25V      1.309V     1.163V
[Falling Waveform]
R_fixture = 50.000
V_fixture = 0.000
V_fixture_min = 0.000
V_fixture_max = 0.000
|  time   V(typ)   V(min)   V(max)
0s        1.249V     1.111V     1.421V
446ps     1.25V      1.111V     1.399V
510ps     1.248V     1.111V     1.194V
562ps     1.214V     1.113V     666.3mV
625ps     1.017V     1.107V     210mV
699ps     417.5mV    1.037V     59.93mV
746ps     189.4mV    893.2mV    28.12mV
848ps     38.9mV     286.4mV    6.164mV
928ps     12.37mV    86.07mV    2.101mV
50ns      3.011uV    6.324uV    2.098uV
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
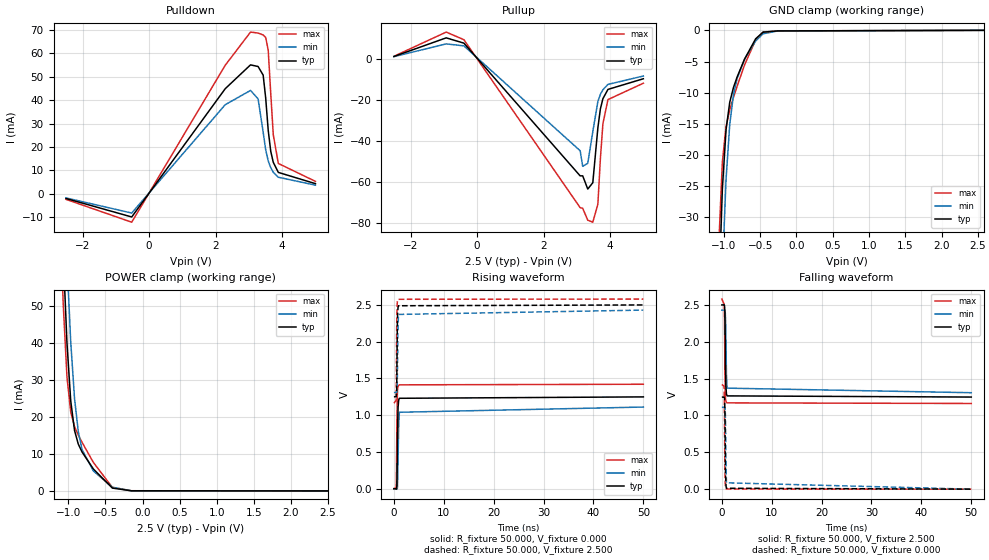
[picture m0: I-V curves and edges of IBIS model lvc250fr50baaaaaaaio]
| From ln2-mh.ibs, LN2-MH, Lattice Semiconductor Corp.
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|   Model lvc250fr50baaaaaaaio
[Model] lvc250fr50baaaaaaaio
Model_type I/O
Polarity   Non-Inverting
Enable   Active-Low
Vinl =  0.700V
Vinh =  1.700V
Vmeas =  1.250V
Cref =  0.0F
Rref =  1.000M
Vref =  0.0V
C_comp   2.000pF   1.500pF   2.500pF
[Temperature Range]   25.000   0.125k   -40.000
[Voltage Range]   2.500V   2.430V   2.580V
[C Comp Corner]
C_comp   2.000pF   1.500pF   2.500pF
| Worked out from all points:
|   slope of the pulldown table from 0 to 0.375 V, typ, clamps not added: 49.6 ohm
|   slope of the pullup table from 0 to 0.375 V, typ, clamps not added: 50.2 ohm
|   GND clamp passes 1 mA (typ) near -0.53 V on its own axis
|   POWER clamp passes 1 mA (typ) near -0.42 V on its own axis
|   rising waveform, R_fixture 50.000, V_fixture 0.000: 20-80 % time 140ps typ, 179ps min, 116ps max; typ from 0 V to 1.25 V
|   rising waveform, R_fixture 50.000, V_fixture 2.500: 20-80 % time 108ps typ, 132ps min, 87.8ps max; typ from 1.25 V to 2.5 V
|   falling waveform, R_fixture 50.000, V_fixture 2.500: 20-80 % time 119ps typ, 149ps min, 102ps max; typ from 2.5 V to 1.25 V
|   falling waveform, R_fixture 50.000, V_fixture 0.000: 20-80 % time 102ps typ, 118ps min, 91.1ps max; typ from 1.25 V to 0 V
[Pulldown]
|Voltage   I(typ)   I(min)   I(max)
-2.5V     -2.069mA   -1.822mA   -2.439mA
-524mV    -9.976mA   -8.302mA   -12.21mA
2.288V    44.9mA     38.05mA    54.93mA
3.048V    55.09mA    44.16mA    69.11mA
3.276V    54.38mA    40.54mA    68.7mA
3.428V    50.7mA     26.28mA    67.88mA
3.504V    40.92mA    18.77mA    66.85mA
3.58V     27.1mA     13.99mA    61.36mA
3.656V    18.12mA    11.09mA    42.86mA
3.732V    13.4mA     9.159mA    25.23mA
3.884V    9.086mA    7.013mA    12.91mA
5V        4.27mA     3.63mA     5.253mA
[Pullup]
|Voltage   I(typ)   I(min)   I(max)
-2.5V     1.032mA    950.4uA    1.125mA
-928mV    10.08mA    7.144mA    12.88mA
-396mV    7.514mA    6.194mA    9.185mA
3.1V      -56.95mA   -44.76mA   -72.38mA
3.176V    -56.93mA   -52.32mA   -72.67mA
3.328V    -63.34mA   -50.84mA   -78.47mA
3.48V     -60.28mA   -35.46mA   -79.44mA
3.632V    -33.66mA   -20.83mA   -70.7mA
3.708V    -24.41mA   -17.34mA   -48.54mA
3.784V    -19.46mA   -15.11mA   -31.56mA
3.936V    -14.95mA   -12.53mA   -19.89mA
5V        -9.784mA   -8.447mA   -11.95mA
[GND_clamp]
|Voltage   I(typ)   I(min)   I(max)
-2.5V     -1.176A    -1.175A    -1.18A
-1.072V   -43.12mA   -59.88mA   -34.84mA
-1.021V   -25.47mA   -38.73mA   -21.11mA
-970mV    -15.91mA   -23.89mA   -15.44mA
-919mV    -11.52mA   -15.06mA   -12.75mA
-868mV    -9.172mA   -10.33mA   -10.76mA
-817mV    -7.47mA    -7.698mA   -8.941mA
-715mV    -4.614mA   -4.632mA   -5.549mA
-562mV    -1.356mA   -1.692mA   -1.528mA
-460mV    -296.7uA   -557.9uA   -261.8uA
-256mV    -93.15uA   -97.62uA   -93.76uA
2.58V     0A         0A         0A
[POWER_clamp]
|Voltage   I(typ)   I(min)   I(max)
-2.498V   1.294A     1.303A     1.292A
-1.121V   95.14mA    121.6mA    80.07mA
-1.07V    64.33mA    89.71mA    50.75mA
-1.019V   40.02mA    62.12mA    30.84mA
-968mV    24.3mA     40.21mA    21.31mA
-917mV    16.34mA    25.01mA    17.39mA
-866mV    12.64mA    16mA       15.07mA
-815mV    10.49mA    11.15mA    13.11mA
-662mV    5.902mA    5.367mA    7.663mA
-407mV    768.2uA    1.002mA    960.5uA
-152mV    40.9uA     39.04uA    48.9uA
2.5V      0A         0A         0A
[Ramp]
| variable   typ   min   max
dV/dt_r   0.765/0.141n   0.681/0.179n   0.870/0.117n
dV/dt_f   0.765/0.120n   0.687/0.151n   0.867/0.102n
R_load = 50.000
[Rising Waveform]
R_fixture = 50.000
V_fixture = 0.000
V_fixture_min = 0.000
V_fixture_max = 0.000
|  time   V(typ)   V(min)   V(max)
0s        1.6uV      6.153uV    2.343uV
463ps     -2.628mV   -232.4uV   15.59mV
510ps     -6.404mV   -39.26uV   218.3mV
598ps     49.28mV    -5.374mV   918.8mV
702ps     575.2mV    7.372mV    1.314V
768ps     928mV      147.8mV    1.373V
832ps     1.106V     399.8mV    1.392V
963ps     1.21V      878.9mV    1.407V
1.093ns   1.23V      1.04V      1.413V
50ns      1.249V     1.111V     1.421V
[Rising Waveform]
R_fixture = 50.000
V_fixture = 2.500
V_fixture_min = 2.430
V_fixture_max = 2.580
|  time   V(typ)   V(min)   V(max)
0s        1.25V      1.309V     1.163V
442ps     1.251V     1.31V      1.2V
477ps     1.249V     1.31V      1.4V
551ps     1.327V     1.309V     2.174V
626ps     1.826V     1.332V     2.478V
676ps     2.179V     1.462V     2.535V
725ps     2.357V     1.712V     2.558V
822ps     2.465V     2.201V     2.572V
921ps     2.489V     2.371V     2.577V
50ns      2.5V       2.43V      2.58V
[Falling Waveform]
R_fixture = 50.000
V_fixture = 2.500
V_fixture_min = 2.430
V_fixture_max = 2.580
|  time   V(typ)   V(min)   V(max)
0s        2.5V       2.43V      2.58V
480ps     2.502V     2.43V      2.509V
541ps     2.491V     2.431V     2.284V
612ps     2.396V     2.43V      1.634V
692ps     2.004V     2.389V     1.289V
749ps     1.609V     2.303V     1.223V
809ps     1.403V     2.091V     1.196V
924ps     1.292V     1.554V     1.177V
1.054ns   1.266V     1.371V     1.171V
50ns      1.25V      1.309V     1.163V
[Falling Waveform]
R_fixture = 50.000
V_fixture = 0.000
V_fixture_min = 0.000
V_fixture_max = 0.000
|  time   V(typ)   V(min)   V(max)
0s        1.249V     1.111V     1.421V
448ps     1.25V      1.111V     1.397V
504ps     1.249V     1.111V     1.23V
562ps     1.214V     1.113V     666.3mV
630ps     986.1mV    1.106V     192.1mV
699ps     417.5mV    1.037V     59.92mV
746ps     189.4mV    893.2mV    28.11mV
848ps     38.89mV    286.4mV    6.155mV
928ps     12.37mV    86.07mV    2.102mV
50ns      1.6uV      6.153uV    2.343uV
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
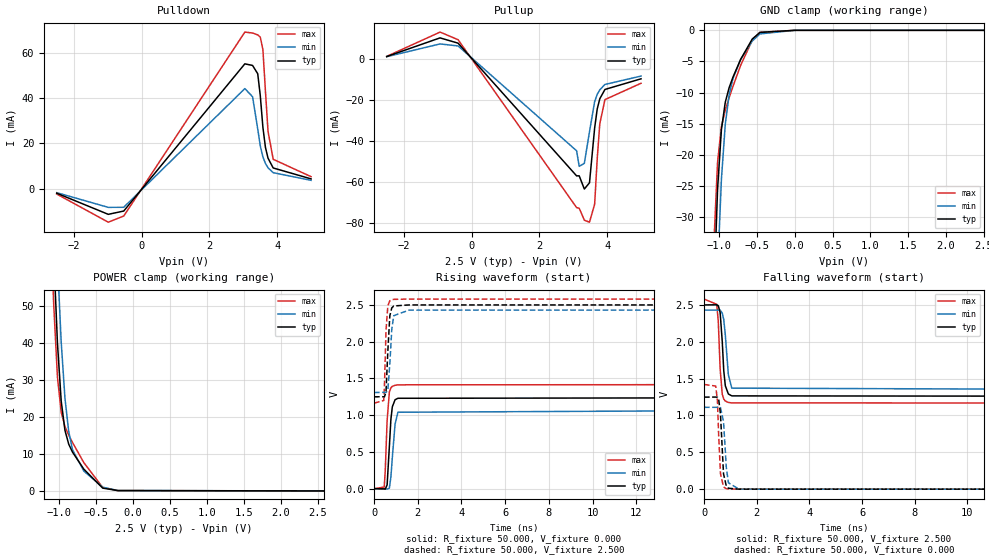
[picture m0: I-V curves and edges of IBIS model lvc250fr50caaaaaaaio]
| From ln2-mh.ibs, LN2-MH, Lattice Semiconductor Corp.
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|   Model lvc250fr50caaaaaaaio
[Model] lvc250fr50caaaaaaaio
Model_type I/O
Polarity   Non-Inverting
Enable   Active-Low
Vinl =  0.700V
Vinh =  1.700V
Vmeas =  1.250V
Cref =  0.0F
Rref =  1.000M
Vref =  0.0V
C_comp   2.000pF   1.500pF   2.500pF
[Temperature Range]   25.000   0.125k   -40.000
[Voltage Range]   2.500V   2.430V   2.580V
[C Comp Corner]
C_comp   2.000pF   1.500pF   2.500pF
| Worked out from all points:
|   slope of the pulldown table from 0 to 0.375 V, typ, clamps not added: 50.2 ohm
|   slope of the pullup table from 0 to 0.375 V, typ, clamps not added: 49.7 ohm
|   GND clamp passes 1 mA (typ) near -0.53 V on its own axis
|   POWER clamp passes 1 mA (typ) near -0.43 V on its own axis
|   rising waveform, R_fixture 50.000, V_fixture 0.000: 20-80 % time 140ps typ, 179ps min, 116ps max; typ from 0 V to 1.25 V
|   rising waveform, R_fixture 50.000, V_fixture 2.500: 20-80 % time 108ps typ, 132ps min, 87.8ps max; typ from 1.25 V to 2.5 V
|   falling waveform, R_fixture 50.000, V_fixture 2.500: 20-80 % time 119ps typ, 149ps min, 102ps max; typ from 2.5 V to 1.25 V
|   falling waveform, R_fixture 50.000, V_fixture 0.000: 20-80 % time 102ps typ, 118ps min, 90.9ps max; typ from 1.25 V to 0 V
[Pulldown]
|Voltage   I(typ)   I(min)   I(max)
-2.5V     -2.064mA   -1.818mA   -2.433mA
-980mV    -11.4mA    -8.318mA   -14.87mA
-524mV    -9.937mA   -8.28mA    -12.15mA
3.048V    55.11mA    44.17mA    69.14mA
3.276V    54.4mA     40.56mA    68.73mA
3.428V    50.72mA    26.29mA    67.91mA
3.504V    40.94mA    18.78mA    66.89mA
3.58V     27.11mA    14mA       61.39mA
3.656V    18.12mA    11.09mA    42.87mA
3.732V    13.4mA     9.163mA    25.24mA
3.884V    9.09mA     7.016mA    12.92mA
5V        4.273mA    3.632mA    5.256mA
[Pullup]
|Voltage   I(typ)   I(min)   I(max)
-2.5V     1.035mA    952.2uA    1.127mA
-928mV    10.1mA     7.158mA    12.91mA
-396mV    7.524mA    6.191mA    9.211mA
3.1V      -56.91mA   -44.73mA   -72.32mA
3.176V    -56.89mA   -52.29mA   -72.61mA
3.328V    -63.3mA    -50.81mA   -78.42mA
3.48V     -60.25mA   -35.45mA   -79.4mA
3.632V    -33.64mA   -20.82mA   -70.66mA
3.708V    -24.4mA    -17.33mA   -48.52mA
3.784V    -19.45mA   -15.11mA   -31.55mA
3.936V    -14.94mA   -12.52mA   -19.88mA
5V        -9.779mA   -8.442mA   -11.94mA
[GND_clamp]
|Voltage   I(typ)   I(min)   I(max)
-2.5V     -1.176A    -1.175A    -1.18A
-1.072V   -43.15mA   -59.89mA   -34.87mA
-1.021V   -25.5mA    -38.75mA   -21.15mA
-970mV    -15.94mA   -23.91mA   -15.48mA
-919mV    -11.55mA   -15.09mA   -12.8mA
-868mV    -9.208mA   -10.36mA   -10.81mA
-817mV    -7.507mA   -7.725mA   -8.99mA
-715mV    -4.652mA   -4.658mA   -5.6mA
-562mV    -1.396mA   -1.715mA   -1.585mA
-460mV    -331.3uA   -573.9uA   -320.1uA
-1mV      -317.6nA   -575.7nA   -335.3nA
2.5V      0A         0A         0A
[POWER_clamp]
|Voltage   I(typ)   I(min)   I(max)
-2.498V   1.294A     1.303A     1.292A
-1.121V   95.13mA    121.6mA    80.05mA
-1.07V    64.32mA    89.7mA     50.73mA
-1.019V   40.01mA    62.11mA    30.82mA
-968mV    24.28mA    40.2mA     21.28mA
-917mV    16.32mA    25mA       17.36mA
-866mV    12.61mA    15.98mA    15.04mA
-815mV    10.46mA    11.14mA    13.07mA
-662mV    5.878mA    5.353mA    7.63mA
-407mV    756.4uA    1.004mA    934.2uA
-203mV    93.32uA    107.9uA    92.71uA
2.58V     0A         0A         0A
[Ramp]
| variable   typ   min   max
dV/dt_r   0.765/0.141n   0.681/0.179n   0.870/0.117n
dV/dt_f   0.765/0.120n   0.687/0.151n   0.867/0.102n
R_load = 50.000
[Rising Waveform]
R_fixture = 50.000
V_fixture = 0.000
V_fixture_min = 0.000
V_fixture_max = 0.000
|  time   V(typ)   V(min)   V(max)
0s        7.351uV    -59.76uV   -25.03uV
467ps     -3.002mV   -286.2uV   22.73mV
514ps     -6.548mV   -147uV     245.9mV
599ps     51.25mV    -5.501mV   925.9mV
702ps     574.5mV    7.308mV    1.315V
772ps     943.6mV    160.8mV    1.374V
837ps     1.114V     421.4mV    1.393V
963ps     1.21V      878.9mV    1.407V
1.093ns   1.23V      1.04V      1.413V
50ns      1.249V     1.111V     1.421V
[Rising Waveform]
R_fixture = 50.000
V_fixture = 2.500
V_fixture_min = 2.430
V_fixture_max = 2.580
|  time   V(typ)   V(min)   V(max)
0s        1.25V      1.309V     1.163V
442ps     1.251V     1.31V      1.2V
477ps     1.249V     1.31V      1.4V
549ps     1.319V     1.309V     2.158V
632ps     1.874V     1.339V     2.488V
723ps     2.352V     1.701V     2.557V
812ps     2.46V      2.166V     2.571V
902ps     2.486V     2.354V     2.576V
1.6ns     2.5V       2.43V      2.58V
50ns      2.5V       2.43V      2.58V
[Falling Waveform]
R_fixture = 50.000
V_fixture = 2.500
V_fixture_min = 2.430
V_fixture_max = 2.580
|  time   V(typ)   V(min)   V(max)
0s        2.5V       2.43V      2.58V
480ps     2.502V     2.43V      2.509V
541ps     2.491V     2.431V     2.284V
612ps     2.396V     2.43V      1.634V
692ps     2.004V     2.389V     1.289V
749ps     1.609V     2.302V     1.223V
809ps     1.403V     2.091V     1.196V
924ps     1.292V     1.554V     1.177V
1.054ns   1.266V     1.371V     1.171V
50ns      1.25V      1.309V     1.163V
[Falling Waveform]
R_fixture = 50.000
V_fixture = 0.000
V_fixture_min = 0.000
V_fixture_max = 0.000
|  time   V(typ)   V(min)   V(max)
0s        1.249V     1.111V     1.421V
446ps     1.25V      1.111V     1.399V
510ps     1.248V     1.111V     1.193V
557ps     1.221V     1.113V     722.5mV
625ps     1.017V     1.107V     209.9mV
740ps     209.1mV    919.5mV    30.87mV
848ps     38.89mV    286.4mV    6.134mV
928ps     12.38mV    86.01mV    2.072mV
1.328ns   205.6uV    635.9uV    92.45uV
50ns      7.351uV    -59.76uV   -25.03uV
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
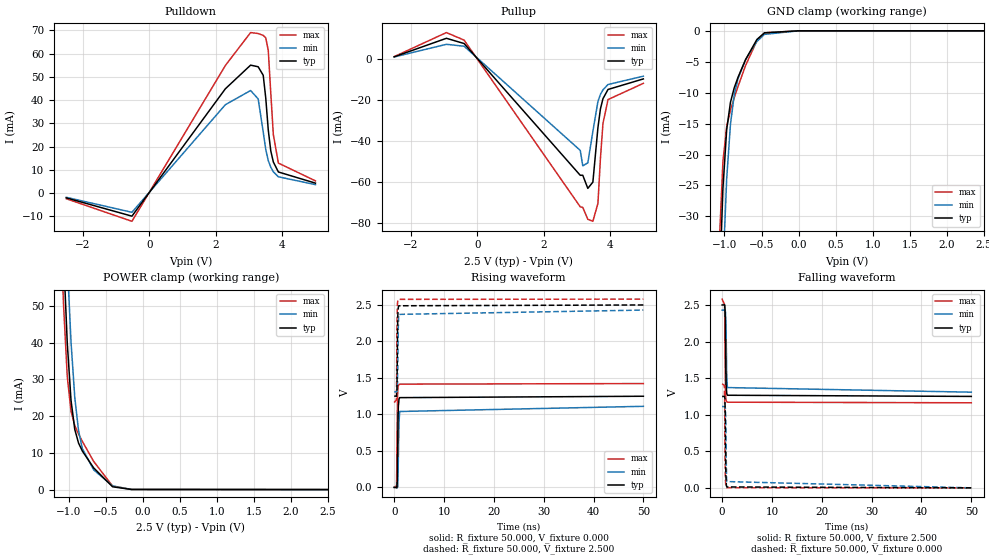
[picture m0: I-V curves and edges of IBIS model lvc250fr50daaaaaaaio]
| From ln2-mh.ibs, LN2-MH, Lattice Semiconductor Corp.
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|   Model lvc250fr50daaaaaaaio
[Model] lvc250fr50daaaaaaaio
Model_type I/O
Polarity   Non-Inverting
Enable   Active-Low
Vinl =  0.700V
Vinh =  1.700V
Vmeas =  1.250V
Cref =  0.0F
Rref =  1.000M
Vref =  0.0V
C_comp   2.000pF   1.500pF   2.500pF
[Temperature Range]   25.000   0.125k   -40.000
[Voltage Range]   2.500V   2.430V   2.580V
[C Comp Corner]
C_comp   2.000pF   1.500pF   2.500pF
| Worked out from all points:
|   slope of the pulldown table from 0 to 0.375 V, typ, clamps not added: 50.2 ohm
|   slope of the pullup table from 0 to 0.375 V, typ, clamps not added: 50.2 ohm
|   GND clamp passes 1 mA (typ) near -0.53 V on its own axis
|   POWER clamp passes 1 mA (typ) near -0.42 V on its own axis
|   rising waveform, R_fixture 50.000, V_fixture 0.000: 20-80 % time 140ps typ, 179ps min, 116ps max; typ from 0 V to 1.25 V
|   rising waveform, R_fixture 50.000, V_fixture 2.500: 20-80 % time 108ps typ, 132ps min, 87.9ps max; typ from 1.25 V to 2.5 V
|   falling waveform, R_fixture 50.000, V_fixture 2.500: 20-80 % time 119ps typ, 149ps min, 102ps max; typ from 2.5 V to 1.25 V
|   falling waveform, R_fixture 50.000, V_fixture 0.000: 20-80 % time 102ps typ, 118ps min, 90.9ps max; typ from 1.25 V to 0 V
[Pulldown]
|Voltage   I(typ)   I(min)   I(max)
-2.5V     -2.064mA   -1.818mA   -2.433mA
-524mV    -9.937mA   -8.28mA    -12.15mA
2.288V    44.9mA     38.05mA    54.93mA
3.048V    55.09mA    44.16mA    69.11mA
3.276V    54.38mA    40.54mA    68.7mA
3.428V    50.7mA     26.28mA    67.88mA
3.504V    40.92mA    18.77mA    66.85mA
3.58V     27.1mA     13.99mA    61.36mA
3.656V    18.12mA    11.09mA    42.86mA
3.732V    13.4mA     9.159mA    25.23mA
3.884V    9.086mA    7.013mA    12.91mA
5V        4.27mA     3.63mA     5.253mA
[Pullup]
|Voltage   I(typ)   I(min)   I(max)
-2.5V     1.032mA    950.4uA    1.125mA
-928mV    10.08mA    7.144mA    12.88mA
-396mV    7.514mA    6.194mA    9.185mA
3.1V      -56.91mA   -44.73mA   -72.32mA
3.176V    -56.89mA   -52.29mA   -72.61mA
3.328V    -63.3mA    -50.81mA   -78.42mA
3.48V     -60.25mA   -35.45mA   -79.4mA
3.632V    -33.64mA   -20.82mA   -70.66mA
3.708V    -24.4mA    -17.33mA   -48.52mA
3.784V    -19.45mA   -15.11mA   -31.55mA
3.936V    -14.94mA   -12.52mA   -19.88mA
5V        -9.779mA   -8.442mA   -11.94mA
[GND_clamp]
|Voltage   I(typ)   I(min)   I(max)
-2.5V     -1.176A    -1.175A    -1.18A
-1.072V   -43.15mA   -59.89mA   -34.87mA
-1.021V   -25.5mA    -38.75mA   -21.15mA
-970mV    -15.94mA   -23.91mA   -15.48mA
-919mV    -11.55mA   -15.09mA   -12.8mA
-868mV    -9.208mA   -10.36mA   -10.81mA
-817mV    -7.507mA   -7.725mA   -8.99mA
-715mV    -4.652mA   -4.658mA   -5.6mA
-562mV    -1.396mA   -1.715mA   -1.585mA
-460mV    -331.3uA   -573.9uA   -320.1uA
-1mV      -317.6nA   -575.7nA   -335.3nA
2.5V      19.47nA    0A         -24.11uA
[POWER_clamp]
|Voltage   I(typ)   I(min)   I(max)
-2.498V   1.294A     1.303A     1.292A
-1.121V   95.14mA    121.6mA    80.07mA
-1.07V    64.33mA    89.71mA    50.75mA
-1.019V   40.02mA    62.12mA    30.84mA
-968mV    24.3mA     40.21mA    21.31mA
-917mV    16.34mA    25.01mA    17.39mA
-866mV    12.64mA    16mA       15.07mA
-815mV    10.49mA    11.15mA    13.11mA
-662mV    5.902mA    5.367mA    7.663mA
-407mV    768.2uA    1.002mA    960.5uA
-152mV    40.9uA     39.04uA    48.9uA
2.5V      0A         0A         24.96uA
[Ramp]
| variable   typ   min   max
dV/dt_r   0.765/0.141n   0.681/0.179n   0.870/0.116n
dV/dt_f   0.765/0.120n   0.687/0.150n   0.867/0.103n
R_load = 50.000
[Rising Waveform]
R_fixture = 50.000
V_fixture = 0.000
V_fixture_min = 0.000
V_fixture_max = 0.000
|  time   V(typ)   V(min)   V(max)
0s        7.351uV    -59.76uV   -25.03uV
467ps     -2.999mV   -286.2uV   22.74mV
514ps     -6.556mV   -147uV     246.2mV
600ps     53.65mV    -5.561mV   934.1mV
702ps     573.7mV    7.308mV    1.316V
768ps     927mV      147.7mV    1.374V
832ps     1.106V     399.7mV    1.394V
963ps     1.21V      878.9mV    1.409V
1.093ns   1.23V      1.04V      1.415V
50ns      1.249V     1.111V     1.423V
[Rising Waveform]
R_fixture = 50.000
V_fixture = 2.500
V_fixture_min = 2.430
V_fixture_max = 2.580
|  time   V(typ)   V(min)   V(max)
0s        1.25V      1.308V     1.163V
442ps     1.251V     1.309V     1.2V
477ps     1.249V     1.309V     1.4V
552ps     1.33V      1.308V     2.182V
626ps     1.825V     1.331V     2.478V
676ps     2.179V     1.46V      2.535V
724ps     2.354V     1.705V     2.557V
822ps     2.465V     2.2V       2.572V
921ps     2.489V     2.371V     2.577V
50ns      2.5V       2.43V      2.58V
[Falling Waveform]
R_fixture = 50.000
V_fixture = 2.500
V_fixture_min = 2.430
V_fixture_max = 2.580
|  time   V(typ)   V(min)   V(max)
0s        2.5V       2.43V      2.58V
480ps     2.502V     2.43V      2.509V
541ps     2.491V     2.431V     2.284V
613ps     2.394V     2.43V      1.625V
687ps     2.041V     2.394V     1.298V
750ps     1.604V     2.3V       1.222V
803ps     1.417V     2.12V      1.198V
924ps     1.292V     1.553V     1.177V
1.054ns   1.266V     1.371V     1.171V
50ns      1.25V      1.308V     1.163V
[Falling Waveform]
R_fixture = 50.000
V_fixture = 0.000
V_fixture_min = 0.000
V_fixture_max = 0.000
|  time   V(typ)   V(min)   V(max)
0s        1.249V     1.111V     1.423V
446ps     1.25V      1.111V     1.401V
510ps     1.248V     1.111V     1.195V
562ps     1.214V     1.113V     667mV
625ps     1.017V     1.107V     210.2mV
699ps     417.8mV    1.037V     59.98mV
746ps     189.6mV    893.1mV    28.13mV
848ps     38.94mV    286.4mV    6.144mV
928ps     12.39mV    86.01mV    2.077mV
50ns      7.351uV    -59.76uV   -25.03uV
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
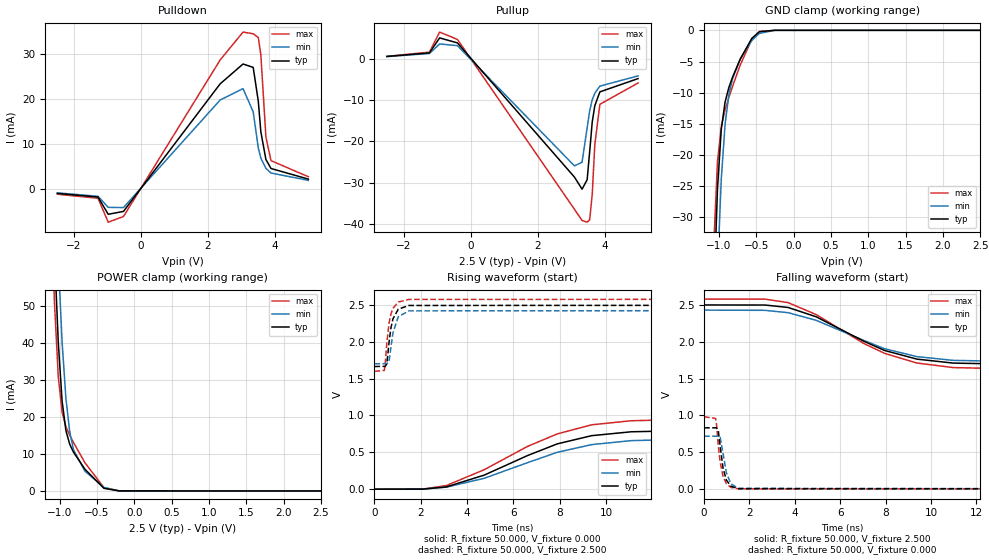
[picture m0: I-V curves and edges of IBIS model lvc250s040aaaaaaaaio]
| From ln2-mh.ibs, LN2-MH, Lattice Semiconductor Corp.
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|   Model lvc250s040aaaaaaaaio
[Model] lvc250s040aaaaaaaaio
Model_type I/O
Polarity   Non-Inverting
Enable   Active-Low
Vinl =  0.700V
Vinh =  1.700V
Vmeas =  1.250V
Cref =  0.0F
Rref =  1.000M
Vref =  0.0V
C_comp   2.000pF   1.500pF   2.500pF
[Temperature Range]   25.000   0.125k   -40.000
[Voltage Range]   2.500V   2.430V   2.580V
[C Comp Corner]
C_comp   2.000pF   1.500pF   2.500pF
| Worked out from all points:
|   slope of the pulldown table from 0 to 0.375 V, typ, clamps not added: 98.4 ohm
|   slope of the pullup table from 0 to 0.375 V, typ, clamps not added: 98.8 ohm
|   GND clamp passes 1 mA (typ) near -0.54 V on its own axis
|   POWER clamp passes 1 mA (typ) near -0.43 V on its own axis
|   rising waveform, R_fixture 50.000, V_fixture 0.000: 20-80 % time 3.91ns typ, 4.14ns min, 3.93ns max; typ from 0 V to 0.832 V
|   rising waveform, R_fixture 50.000, V_fixture 2.500: 20-80 % time 239ps typ, 250ps min, 230ps max; typ from 1.67 V to 2.5 V
|   falling waveform, R_fixture 50.000, V_fixture 2.500: 20-80 % time 3.46ns typ, 3.59ns min, 3.53ns max; typ from 2.5 V to 1.67 V
|   falling waveform, R_fixture 50.000, V_fixture 0.000: 20-80 % time 248ps typ, 259ps min, 240ps max; typ from 0.832 V to 0 V
[Pulldown]
|Voltage   I(typ)   I(min)   I(max)
-2.5V     -1.032mA   -909.3uA   -1.218mA
-1.284V   -1.851mA   -1.671mA   -2.11mA
-980mV    -5.675mA   -4.136mA   -7.436mA
-524mV    -5.036mA   -4.185mA   -6.17mA
2.364V    23.34mA    19.74mA    28.65mA
3.048V    27.76mA    22.28mA    34.86mA
3.352V    27mA       17.12mA    34.49mA
3.504V    19.49mA    9.078mA    33.65mA
3.58V     12.69mA    6.807mA    29.84mA
3.732V    6.511mA    4.539mA    11.47mA
3.884V    4.51mA     3.504mA    6.259mA
5V        2.148mA    1.867mA    2.677mA
[Pullup]
|Voltage   I(typ)   I(min)   I(max)
-2.5V     516.3uA    476uA      541.2uA
-1.232V   1.373mA    1.231mA    1.559mA
-928mV    5.006mA    3.543mA    6.413mA
-396mV    3.796mA    3.125mA    4.64mA
3.1V      -28.68mA   -25.97mA   -36.47mA
3.328V    -31.61mA   -25.1mA    -39.18mA
3.48V     -29.32mA   -16.75mA   -39.6mA
3.556V    -22.47mA   -12.59mA   -38.99mA
3.632V    -15.36mA   -9.98mA    -32.87mA
3.708V    -11.44mA   -8.392mA   -20.9mA
3.86V     -8.058mA   -6.662mA   -11.07mA
5V        -4.848mA   -4.198mA   -5.912mA
[GND_clamp]
|Voltage   I(typ)   I(min)   I(max)
-2.5V     -1.176A    -1.175A    -1.18A
-1.072V   -43.12mA   -59.87mA   -34.84mA
-1.021V   -25.46mA   -38.72mA   -21.1mA
-970mV    -15.9mA    -23.88mA   -15.42mA
-919mV    -11.5mA    -15.05mA   -12.74mA
-868mV    -9.155mA   -10.31mA   -10.74mA
-817mV    -7.451mA   -7.678mA   -8.924mA
-715mV    -4.588mA   -4.605mA   -5.525mA
-562mV    -1.31mA    -1.648mA   -1.483mA
-460mV    -221.2uA   -492.9uA   -183.3uA
-256mV    -336.9nA   -5.429uA   -53.89nA
2.5V      0A         0A         0A
[POWER_clamp]
|Voltage   I(typ)   I(min)   I(max)
-2.498V   1.294A     1.303A     1.292A
-1.121V   95.13mA    121.6mA    80.05mA
-1.07V    64.31mA    89.69mA    50.73mA
-1.019V   40mA       62.1mA     30.81mA
-968mV    24.27mA    40.19mA    21.27mA
-917mV    16.31mA    24.99mA    17.34mA
-866mV    12.6mA     15.97mA    15.03mA
-815mV    10.45mA    11.12mA    13.06mA
-662mV    5.856mA    5.328mA    7.611mA
-407mV    698.4uA    949.4uA    879.7uA
-203mV    1.851uA    18.03uA    575.7nA
2.5V      0A         0A         0A
[Ramp]
| variable   typ   min   max
dV/dt_r   0.510/3.926n   0.440/4.171n   0.602/3.958n
dV/dt_f   0.511/3.487n   0.446/3.628n   0.601/3.542n
R_load = 50.000
[Rising Waveform]
R_fixture = 50.000
V_fixture = 0.000
V_fixture_min = 0.000
V_fixture_max = 0.000
|  time   V(typ)   V(min)   V(max)
0s        2.224uV    10.27uV    1.34uV
2.086ns   464.8uV    1.291mV    1.178mV
3.105ns   30.76mV    27.24mV    49.38mV
4.742ns   191.1mV    147.9mV    264.6mV
6.607ns   456mV      359.6mV    580.1mV
7.892ns   614.7mV    500.5mV    750.2mV
9.375ns   726mV      604.5mV    873.2mV
11.08ns   778.8mV    658.8mV    928.9mV
18.61ns   828.8mV    715mV      978.1mV
50ns      832.5mV    719mV      983.1mV
[Rising Waveform]
R_fixture = 50.000
V_fixture = 2.500
V_fixture_min = 2.430
V_fixture_max = 2.580
|  time   V(typ)   V(min)   V(max)
0s        1.665V     1.702V     1.599V
426ps     1.666V     1.703V     1.612V
457ps     1.665V     1.703V     1.67V
536ps     1.701V     1.703V     1.989V
632ps     1.997V     1.732V     2.255V
712ps     2.189V     1.925V     2.377V
800ps     2.312V     2.124V     2.455V
1.03ns    2.443V     2.341V     2.54V
1.49ns    2.493V     2.42V      2.575V
50ns      2.5V       2.43V      2.58V
[Falling Waveform]
R_fixture = 50.000
V_fixture = 2.500
V_fixture_min = 2.430
V_fixture_max = 2.580
|  time   V(typ)   V(min)   V(max)
0s        2.5V       2.43V      2.58V
2.681ns   2.499V     2.427V     2.579V
3.701ns   2.466V     2.395V     2.532V
4.934ns   2.34V      2.292V     2.37V
7.043ns   2.007V     2.018V     1.976V
7.955ns   1.882V     1.906V     1.843V
9.375ns   1.765V     1.799V     1.712V
10.98ns   1.711V     1.748V     1.65V
18.3ns    1.668V     1.705V     1.602V
50ns      1.665V     1.702V     1.599V
[Falling Waveform]
R_fixture = 50.000
V_fixture = 0.000
V_fixture_min = 0.000
V_fixture_max = 0.000
|  time   V(typ)   V(min)   V(max)
0s        832.5mV    719mV      983.1mV
506ps     832.6mV    718.8mV    959.7mV
547ps     832.2mV    719mV      881.3mV
625ps     796.4mV    719.3mV    591.6mV
706ps     587.2mV    706.9mV    372.2mV
835ps     285.9mV    488.7mV    173.8mV
981ps     123.3mV    222.6mV    74.47mV
1.181ns   39.84mV    72.52mV    23.98mV
1.521ns   6.228mV    11.28mV    3.847mV
50ns      2.224uV    10.27uV    1.34uV
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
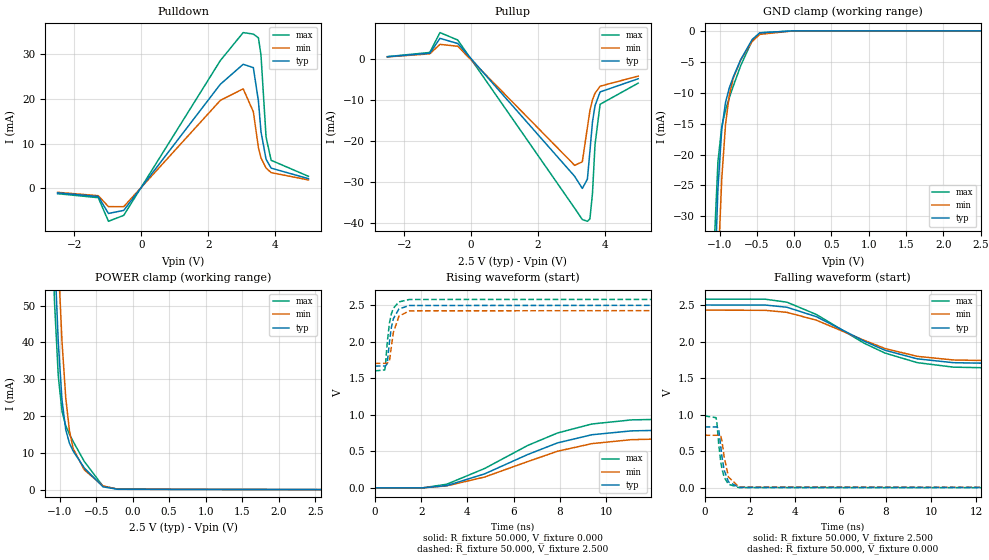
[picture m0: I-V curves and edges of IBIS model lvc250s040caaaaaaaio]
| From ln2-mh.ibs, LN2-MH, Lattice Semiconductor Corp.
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|   Model lvc250s040caaaaaaaio
[Model] lvc250s040caaaaaaaio
Model_type I/O
Polarity   Non-Inverting
Enable   Active-Low
Vinl =  0.700V
Vinh =  1.700V
Vmeas =  1.250V
Cref =  0.0F
Rref =  1.000M
Vref =  0.0V
C_comp   2.000pF   1.500pF   2.500pF
[Temperature Range]   25.000   0.125k   -40.000
[Voltage Range]   2.500V   2.430V   2.580V
[C Comp Corner]
C_comp   2.000pF   1.500pF   2.500pF
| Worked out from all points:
|   slope of the pulldown table from 0 to 0.375 V, typ, clamps not added: 101 ohm
|   slope of the pullup table from 0 to 0.375 V, typ, clamps not added: 98.8 ohm
|   GND clamp passes 1 mA (typ) near -0.53 V on its own axis
|   POWER clamp passes 1 mA (typ) near -0.43 V on its own axis
|   rising waveform, R_fixture 50.000, V_fixture 0.000: 20-80 % time 3.91ns typ, 4.15ns min, 3.93ns max; typ from 0 V to 0.832 V
|   rising waveform, R_fixture 50.000, V_fixture 2.500: 20-80 % time 239ps typ, 250ps min, 230ps max; typ from 1.67 V to 2.5 V
|   falling waveform, R_fixture 50.000, V_fixture 2.500: 20-80 % time 3.46ns typ, 3.59ns min, 3.53ns max; typ from 2.5 V to 1.67 V
|   falling waveform, R_fixture 50.000, V_fixture 0.000: 20-80 % time 247ps typ, 259ps min, 240ps max; typ from 0.832 V to 0 V
[Pulldown]
|Voltage   I(typ)   I(min)   I(max)
-2.5V     -1.026mA   -903.5uA   -1.21mA
-1.284V   -1.838mA   -1.659mA   -2.096mA
-980mV    -5.631mA   -4.103mA   -7.38mA
-524mV    -4.941mA   -4.114mA   -6.055mA
2.364V    23.25mA    19.65mA    28.55mA
3.048V    27.73mA    22.25mA    34.82mA
3.352V    26.98mA    17.11mA    34.48mA
3.504V    19.48mA    9.072mA    33.64mA
3.58V     12.68mA    6.803mA    29.83mA
3.732V    6.508mA    4.536mA    11.47mA
3.884V    4.508mA    3.501mA    6.258mA
5V        2.148mA    1.866mA    2.677mA
[Pullup]
|Voltage   I(typ)   I(min)   I(max)
-2.5V     515.5uA    475uA      540.5uA
-1.232V   1.371mA    1.228mA    1.557mA
-928mV    4.994mA    3.531mA    6.402mA
-396mV    3.735mA    3.069mA    4.582mA
3.1V      -28.6mA    -25.92mA   -36.36mA
3.328V    -31.55mA   -25.06mA   -39.11mA
3.48V     -29.28mA   -16.73mA   -39.54mA
3.556V    -22.44mA   -12.58mA   -38.93mA
3.632V    -15.34mA   -9.966mA   -32.82mA
3.708V    -11.42mA   -8.38mA    -20.87mA
3.86V     -8.047mA   -6.653mA   -11.06mA
5V        -4.842mA   -4.193mA   -5.904mA
[GND_clamp]
|Voltage   I(typ)   I(min)   I(max)
-2.5V     -1.176A    -1.175A    -1.18A
-1.072V   -43.15mA   -59.89mA   -34.87mA
-1.021V   -25.5mA    -38.75mA   -21.15mA
-970mV    -15.94mA   -23.91mA   -15.48mA
-919mV    -11.55mA   -15.09mA   -12.8mA
-868mV    -9.208mA   -10.36mA   -10.81mA
-817mV    -7.507mA   -7.725mA   -8.99mA
-715mV    -4.652mA   -4.658mA   -5.6mA
-562mV    -1.396mA   -1.715mA   -1.585mA
-460mV    -331.3uA   -573.9uA   -320.1uA
-1mV      -317.6nA   -575.7nA   -335.3nA
2.5V      0A         0A         0A
[POWER_clamp]
|Voltage   I(typ)   I(min)   I(max)
-2.498V   1.294A     1.303A     1.292A
-1.121V   95.13mA    121.6mA    80.05mA
-1.07V    64.32mA    89.7mA     50.73mA
-1.019V   40.01mA    62.11mA    30.82mA
-968mV    24.28mA    40.2mA     21.28mA
-917mV    16.32mA    25mA       17.36mA
-866mV    12.61mA    15.98mA    15.04mA
-815mV    10.46mA    11.14mA    13.07mA
-662mV    5.878mA    5.353mA    7.63mA
-407mV    756.4uA    1.004mA    934.2uA
-203mV    93.32uA    107.9uA    92.71uA
2.58V     0A         0A         0A
[Ramp]
| variable   typ   min   max
dV/dt_r   0.510/3.926n   0.440/4.171n   0.602/3.949n
dV/dt_f   0.511/3.482n   0.446/3.628n   0.601/3.542n
R_load = 50.000
[Rising Waveform]
R_fixture = 50.000
V_fixture = 0.000
V_fixture_min = 0.000
V_fixture_max = 0.000
|  time   V(typ)   V(min)   V(max)
0s        9.948uV    -75.95uV   -34.58uV
2.086ns   472.5uV    1.204mV    1.14mV
3.105ns   30.77mV    27.16mV    49.33mV
4.742ns   191.1mV    147.8mV    264.6mV
6.607ns   456mV      359.6mV    580mV
7.892ns   614.7mV    500.4mV    750.2mV
9.375ns   726mV      604.5mV    873.1mV
11.08ns   778.8mV    658.8mV    928.9mV
18.61ns   828.8mV    715mV      978.1mV
50ns      832.5mV    719mV      983.1mV
[Rising Waveform]
R_fixture = 50.000
V_fixture = 2.500
V_fixture_min = 2.430
V_fixture_max = 2.580
|  time   V(typ)   V(min)   V(max)
0s        1.665V     1.702V     1.599V
426ps     1.666V     1.703V     1.612V
457ps     1.665V     1.703V     1.67V
535ps     1.699V     1.703V     1.985V
632ps     1.997V     1.732V     2.255V
712ps     2.189V     1.925V     2.377V
800ps     2.312V     2.124V     2.455V
1.041ns   2.446V     2.346V     2.542V
1.49ns    2.493V     2.42V      2.575V
50ns      2.5V       2.43V      2.58V
[Falling Waveform]
R_fixture = 50.000
V_fixture = 2.500
V_fixture_min = 2.430
V_fixture_max = 2.580
|  time   V(typ)   V(min)   V(max)
0s        2.5V       2.43V      2.58V
2.677ns   2.499V     2.427V     2.579V
3.637ns   2.469V     2.399V     2.538V
4.935ns   2.34V      2.292V     2.37V
7.047ns   2.006V     2.017V     1.977V
7.965ns   1.881V     1.905V     1.843V
9.385ns   1.764V     1.798V     1.712V
10.99ns   1.711V     1.748V     1.65V
19.27ns   1.667V     1.705V     1.601V
50ns      1.665V     1.702V     1.599V
[Falling Waveform]
R_fixture = 50.000
V_fixture = 0.000
V_fixture_min = 0.000
V_fixture_max = 0.000
|  time   V(typ)   V(min)   V(max)
0s        832.5mV    719mV      983.1mV
506ps     832.6mV    718.8mV    959.7mV
547ps     832.2mV    719mV      881.3mV
625ps     796.4mV    719.3mV    591.6mV
711ps     571.7mV    704.4mV    361.3mV
765ps     426.4mV    649.1mV    262.6mV
863ps     243.2mV    425mV      147.4mV
1.052ns   82.34mV    149.2mV    49.61mV
1.523ns   6.17mV     11.08mV    3.773mV
50ns      9.948uV    -75.95uV   -34.58uV
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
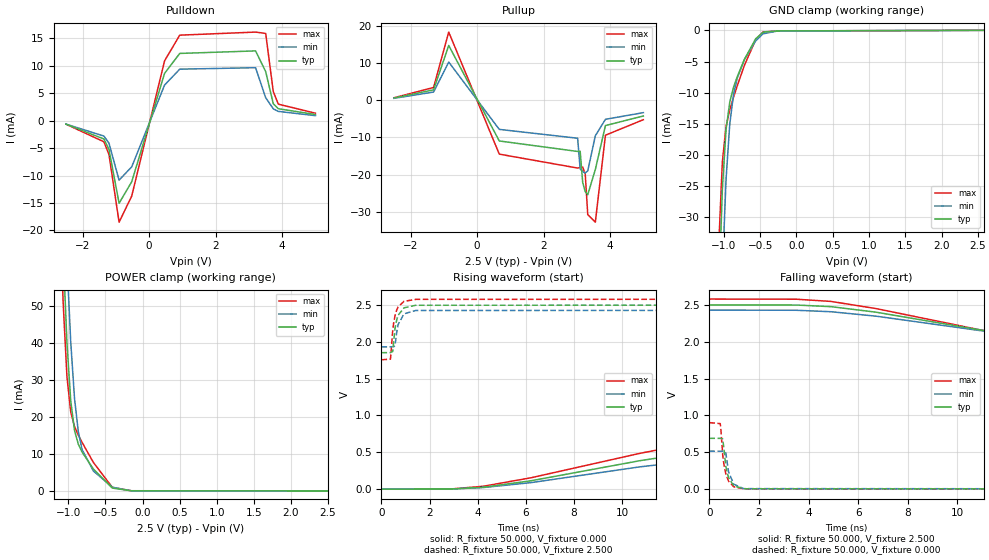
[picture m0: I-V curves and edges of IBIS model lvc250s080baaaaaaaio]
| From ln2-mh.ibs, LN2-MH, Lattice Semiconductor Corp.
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|   Model lvc250s080baaaaaaaio
[Model] lvc250s080baaaaaaaio
Model_type I/O
Polarity   Non-Inverting
Enable   Active-Low
Vinl =  0.700V
Vinh =  1.700V
Vmeas =  1.250V
Cref =  0.0F
Rref =  1.000M
Vref =  0.0V
C_comp   2.000pF   1.500pF   2.500pF
[Temperature Range]   25.000   0.125k   -40.000
[Voltage Range]   2.500V   2.430V   2.580V
[C Comp Corner]
C_comp   2.000pF   1.500pF   2.500pF
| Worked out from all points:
|   slope of the pulldown table from 0 to 0.375 V, typ, clamps not added: 52.4 ohm
|   slope of the pullup table from 0 to 0.375 V, typ, clamps not added: 52.6 ohm
|   GND clamp passes 1 mA (typ) near -0.53 V on its own axis
|   POWER clamp passes 1 mA (typ) near -0.42 V on its own axis
|   rising waveform, R_fixture 50.000, V_fixture 0.000: 20-80 % time 7.59ns typ, 7.24ns min, 8.16ns max; typ from 0 V to 0.69 V
|   rising waveform, R_fixture 50.000, V_fixture 2.500: 20-80 % time 205ps typ, 209ps min, 201ps max; typ from 1.85 V to 2.5 V
|   falling waveform, R_fixture 50.000, V_fixture 2.500: 20-80 % time 7.45ns typ, 7.08ns min, 7.94ns max; typ from 2.5 V to 1.85 V
|   falling waveform, R_fixture 50.000, V_fixture 0.000: 20-80 % time 207ps typ, 211ps min, 205ps max; typ from 0.69 V to 0 V
[Pulldown]
|Voltage   I(typ)   I(min)   I(max)
-2.5V     -628.6uA   -618.3uA   -638.7uA
-1.36V    -3.338mA   -2.803mA   -3.847mA
-1.208V   -5.22mA    -4.093mA   -6.151mA
-904mV    -15.05mA   -10.84mA   -18.5mA
-524mV    -11.13mA   -8.409mA   -13.74mA
464mV     8.625mA    6.498mA    10.91mA
920mV     12.26mA    9.392mA    15.59mA
3.2V      12.72mA    9.659mA    16.15mA
3.504V    8.942mA    4.189mA    15.9mA
3.732V    3.089mA    2.164mA    5.322mA
3.884V    2.182mA    1.692mA    3.014mA
5V        1.117mA    919.8uA    1.364mA
[Pullup]
|Voltage   I(typ)   I(min)   I(max)
-2.5V     561.9uA    476.1uA    623.6uA
-1.308V   2.763mA    2.162mA    3.396mA
-852mV    14.68mA    10.22mA    18.28mA
668mV     -10.98mA   -7.87mA    -14.52mA
3.024V    -13.8mA    -10.25mA   -18.26mA
3.1V      -13.74mA   -18.5mA    -18.12mA
3.176V    -22.13mA   -19.21mA   -18mA
3.252V    -24.59mA   -19.59mA   -19.85mA
3.328V    -25.44mA   -19.02mA   -30.77mA
3.556V    -18.66mA   -9.581mA   -32.81mA
3.86V     -6.837mA   -5.161mA   -9.435mA
5V        -4.268mA   -3.368mA   -5.262mA
[GND_clamp]
|Voltage   I(typ)   I(min)   I(max)
-2.5V     -1.176A    -1.175A    -1.18A
-1.072V   -43.12mA   -59.88mA   -34.84mA
-1.021V   -25.47mA   -38.73mA   -21.11mA
-970mV    -15.91mA   -23.89mA   -15.44mA
-919mV    -11.52mA   -15.06mA   -12.75mA
-868mV    -9.172mA   -10.33mA   -10.76mA
-817mV    -7.47mA    -7.698mA   -8.941mA
-715mV    -4.614mA   -4.632mA   -5.549mA
-562mV    -1.356mA   -1.692mA   -1.528mA
-460mV    -296.7uA   -557.9uA   -261.8uA
-256mV    -93.15uA   -97.62uA   -93.76uA
2.58V     0A         0A         0A
[POWER_clamp]
|Voltage   I(typ)   I(min)   I(max)
-2.498V   1.294A     1.303A     1.292A
-1.121V   95.14mA    121.6mA    80.07mA
-1.07V    64.33mA    89.71mA    50.75mA
-1.019V   40.02mA    62.12mA    30.84mA
-968mV    24.3mA     40.21mA    21.31mA
-917mV    16.34mA    25.01mA    17.39mA
-866mV    12.64mA    16mA       15.07mA
-815mV    10.49mA    11.15mA    13.11mA
-662mV    5.902mA    5.367mA    7.663mA
-407mV    768.2uA    1.002mA    960.5uA
-152mV    40.9uA     39.04uA    48.9uA
2.5V      0A         0A         0A
[Ramp]
| variable   typ   min   max
dV/dt_r   0.425/7.591n   0.316/7.255n   0.555/8.166n
dV/dt_f   0.399/7.477n   0.307/7.102n   0.507/7.951n
R_load = 50.000
[Rising Waveform]
R_fixture = 50.000
V_fixture = 0.000
V_fixture_min = 0.000
V_fixture_max = 0.000
|  time   V(typ)   V(min)   V(max)
0s        43.84uV    51.54uV    40.52uV
2.898ns   1.681mV    2.664mV    2.962mV
4.238ns   26.06mV    22.24mV    39.75mV
6.217ns   114.1mV    88.82mV    155mV
10.73ns   386.1mV    302.6mV    485.7mV
13.37ns   518.3mV    400.3mV    653.1mV
16.14ns   611.3mV    466.2mV    778.4mV
19.59ns   671.8mV    503.9mV    868.8mV
23.04ns   681.8mV    509.2mV    894.1mV
50ns      690.2mV    515.7mV    902.9mV
[Rising Waveform]
R_fixture = 50.000
V_fixture = 2.500
V_fixture_min = 2.430
V_fixture_max = 2.580
|  time   V(typ)   V(min)   V(max)
0s        1.852V     1.931V     1.756V
376ps     1.854V     1.932V     1.765V
470ps     1.869V     1.933V     2.16V
508ps     2.006V     1.933V     2.258V
565ps     2.183V     1.948V     2.357V
635ps     2.3V       2.134V     2.433V
695ps     2.361V     2.235V     2.475V
938ps     2.461V     2.38V      2.549V
1.425ns   2.496V     2.425V     2.576V
50ns      2.5V       2.43V      2.58V
[Falling Waveform]
R_fixture = 50.000
V_fixture = 2.500
V_fixture_min = 2.430
V_fixture_max = 2.580
|  time   V(typ)   V(min)   V(max)
0s        2.5V       2.43V      2.58V
3.503ns   2.499V     2.428V     2.578V
4.906ns   2.477V     2.408V     2.548V
6.717ns   2.402V     2.348V     2.451V
11.24ns   2.143V     2.137V     2.14V
13.95ns   2.013V     2.038V     1.981V
16.93ns   1.918V     1.972V     1.856V
19.75ns   1.873V     1.945V     1.788V
23.55ns   1.86V      1.938V     1.762V
50ns      1.852V     1.931V     1.756V
[Falling Waveform]
R_fixture = 50.000
V_fixture = 0.000
V_fixture_min = 0.000
V_fixture_max = 0.000
|  time   V(typ)   V(min)   V(max)
0s        690.2mV    515.7mV    902.9mV
438ps     689.7mV    515.4mV    890mV
463ps     689.8mV    515.3mV    820.3mV
537ps     682.2mV    515.3mV    472mV
583ps     563.9mV    515.4mV    344.4mV
663ps     309.1mV    490.6mV    208.8mV
773ps     155.4mV    236.7mV    109mV
982ps     46.91mV    67.95mV    33.07mV
1.383ns   5.157mV    7.522mV    3.643mV
50ns      43.84uV    51.54uV    40.52uV
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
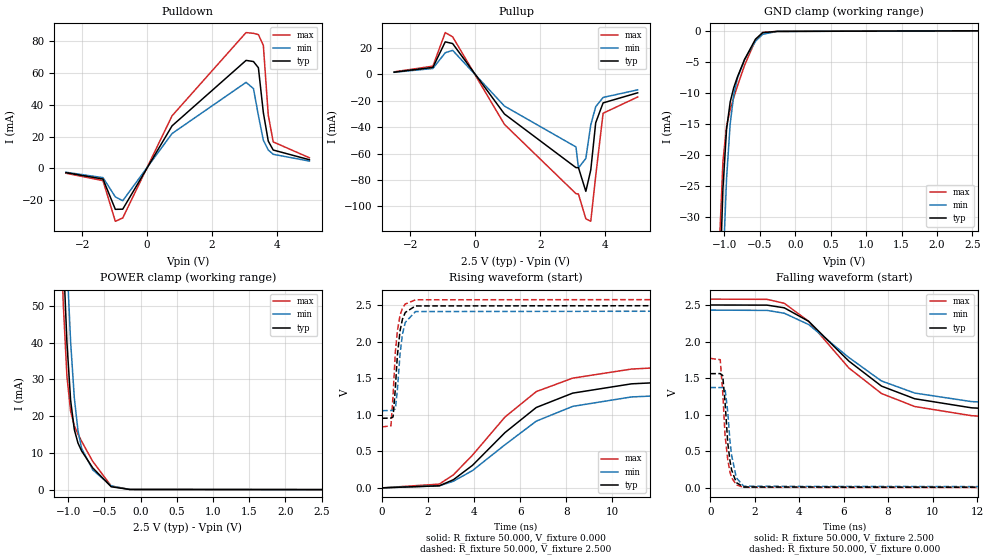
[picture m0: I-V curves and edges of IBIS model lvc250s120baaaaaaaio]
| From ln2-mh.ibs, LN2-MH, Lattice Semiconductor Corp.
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|   Model lvc250s120baaaaaaaio
[Model] lvc250s120baaaaaaaio
Model_type I/O
Polarity   Non-Inverting
Enable   Active-Low
Vinl =  0.700V
Vinh =  1.700V
Vmeas =  1.250V
Cref =  0.0F
Rref =  1.000M
Vref =  0.0V
C_comp   2.000pF   1.500pF   2.500pF
[Temperature Range]   25.000   0.125k   -40.000
[Voltage Range]   2.500V   2.430V   2.580V
[C Comp Corner]
C_comp   2.000pF   1.500pF   2.500pF
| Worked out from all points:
|   slope of the pulldown table from 0 to 0.375 V, typ, clamps not added: 26 ohm
|   slope of the pullup table from 0 to 0.375 V, typ, clamps not added: 26 ohm
|   GND clamp passes 1 mA (typ) near -0.53 V on its own axis
|   POWER clamp passes 1 mA (typ) near -0.42 V on its own axis
|   rising waveform, R_fixture 50.000, V_fixture 0.000: 20-80 % time 3.81ns typ, 3.98ns min, 3.67ns max; typ from 0 V to 1.56 V
|   rising waveform, R_fixture 50.000, V_fixture 2.500: 20-80 % time 245ps typ, 254ps min, 237ps max; typ from 0.951 V to 2.5 V
|   falling waveform, R_fixture 50.000, V_fixture 2.500: 20-80 % time 3.93ns typ, 3.98ns min, 3.86ns max; typ from 2.5 V to 0.951 V
|   falling waveform, R_fixture 50.000, V_fixture 0.000: 20-80 % time 272ps typ, 283ps min, 263ps max; typ from 1.56 V to 0 V
[Pulldown]
|Voltage   I(typ)   I(min)   I(max)
-2.5V     -2.713mA   -2.452mA   -3.097mA
-1.36V    -6.741mA   -5.868mA   -7.75mA
-980mV    -25.81mA   -17.97mA   -33.33mA
-752mV    -25.71mA   -20.38mA   -31.24mA
768mV     26.73mA    21.9mA     33.04mA
3.048V    67.91mA    54.09mA    85.42mA
3.276V    67.19mA    50.17mA    84.93mA
3.428V    63.28mA    33.25mA    84.14mA
3.58V     35.13mA    17.7mA     77.39mA
3.732V    17.13mA    11.54mA    33.54mA
3.884V    11.51mA    8.816mA    16.62mA
5V        5.403mA    4.564mA    6.641mA
[Pullup]
|Voltage   I(typ)   I(min)   I(max)
-2.5V     1.549mA    1.434mA    1.804mA
-1.308V   5.154mA    4.335mA    6.097mA
-928mV    24.49mA    16.24mA    31.51mA
-700mV    23.18mA    18.06mA    28.28mA
896mV     -30.11mA   -24.12mA   -37.97mA
3.1V      -70.69mA   -55.04mA   -90.38mA
3.176V    -70.65mA   -70.9mA    -90.64mA
3.404V    -88.64mA   -63.76mA   -109.4mA
3.556V    -72.53mA   -38.3mA    -111.3mA
3.708V    -36.71mA   -24.6mA    -77mA
3.936V    -21.7mA    -17.58mA   -29.53mA
5V        -14.08mA   -11.84mA   -17.25mA
[GND_clamp]
|Voltage   I(typ)   I(min)   I(max)
-2.5V     -1.176A    -1.175A    -1.18A
-1.072V   -43.12mA   -59.88mA   -34.84mA
-1.021V   -25.47mA   -38.73mA   -21.11mA
-970mV    -15.91mA   -23.89mA   -15.44mA
-919mV    -11.52mA   -15.06mA   -12.75mA
-868mV    -9.172mA   -10.33mA   -10.76mA
-817mV    -7.47mA    -7.698mA   -8.941mA
-715mV    -4.614mA   -4.632mA   -5.549mA
-562mV    -1.356mA   -1.692mA   -1.528mA
-460mV    -296.7uA   -557.9uA   -261.8uA
-256mV    -93.15uA   -97.62uA   -93.76uA
2.58V     0A         0A         0A
[POWER_clamp]
|Voltage   I(typ)   I(min)   I(max)
-2.498V   1.294A     1.303A     1.292A
-1.121V   95.14mA    121.6mA    80.07mA
-1.07V    64.33mA    89.71mA    50.75mA
-1.019V   40.02mA    62.12mA    30.84mA
-968mV    24.3mA     40.21mA    21.31mA
-917mV    16.34mA    25.01mA    17.39mA
-866mV    12.64mA    16mA       15.07mA
-815mV    10.49mA    11.15mA    13.11mA
-662mV    5.902mA    5.367mA    7.663mA
-407mV    768.2uA    1.002mA    960.5uA
-152mV    40.9uA     39.04uA    48.9uA
2.5V      0A         0A         0A
[Ramp]
| variable   typ   min   max
dV/dt_r   0.959/3.814n   0.842/3.981n   1.086/3.678n
dV/dt_f   0.952/3.925n   0.845/3.976n   1.072/3.859n
R_load = 50.000
[Rising Waveform]
R_fixture = 50.000
V_fixture = 0.000
V_fixture_min = 0.000
V_fixture_max = 0.000
|  time   V(typ)   V(min)   V(max)
0s        29.03uV    32.39uV    24.96uV
2.486ns   28.31mV    27.71mV    51.31mV
3.099ns   111.5mV    91.01mV    178.5mV
3.929ns   308.8mV    236.8mV    448.3mV
5.339ns   756.1mV    590mV      969.1mV
6.696ns   1.099V     912.2mV    1.316V
8.276ns   1.295V     1.114V     1.5V
10.83ns   1.422V     1.243V     1.624V
18.86ns   1.546V     1.353V     1.757V
50ns      1.561V     1.371V     1.77V
[Rising Waveform]
R_fixture = 50.000
V_fixture = 2.500
V_fixture_min = 2.430
V_fixture_max = 2.580
|  time   V(typ)   V(min)   V(max)
0s        950.8mV    1.055V     833.1mV
387ps     954.5mV    1.058V     847.9mV
478ps     969.3mV    1.06V      1.261V
577ps     1.355V     1.08V      1.849V
663ps     1.801V     1.327V     2.137V
784ps     2.152V     1.84V      2.364V
887ps     2.307V     2.102V     2.456V
1.009ns   2.398V     2.262V     2.513V
1.453ns   2.487V     2.41V      2.571V
50ns      2.5V       2.43V      2.58V
[Falling Waveform]
R_fixture = 50.000
V_fixture = 2.500
V_fixture_min = 2.430
V_fixture_max = 2.580
|  time   V(typ)   V(min)   V(max)
0s        2.5V       2.43V      2.58V
2.554ns   2.498V     2.426V     2.577V
3.332ns   2.461V     2.387V     2.523V
4.426ns   2.277V     2.233V     2.277V
6.236ns   1.733V     1.782V     1.639V
7.704ns   1.391V     1.461V     1.29V
9.2ns     1.218V     1.296V     1.112V
11.76ns   1.094V     1.179V     986.5mV
20.09ns   964.1mV    1.073V     842.8mV
50ns      950.8mV    1.055V     833.1mV
[Falling Waveform]
R_fixture = 50.000
V_fixture = 0.000
V_fixture_min = 0.000
V_fixture_max = 0.000
|  time   V(typ)   V(min)   V(max)
0s        1.561V     1.371V     1.77V
449ps     1.562V     1.371V     1.752V
560ps     1.535V     1.371V     1.313V
666ps     1.172V     1.354V     715.9mV
786ps     618.9mV    1.043V     387.5mV
886ps     373.5mV    645.6mV    216.7mV
959ps     247.4mV    448.6mV    140.8mV
1.174ns   71.75mV    137.5mV    40.92mV
1.506ns   11.72mV    21.95mV    6.99mV
50ns      29.03uV    32.39uV    24.96uV
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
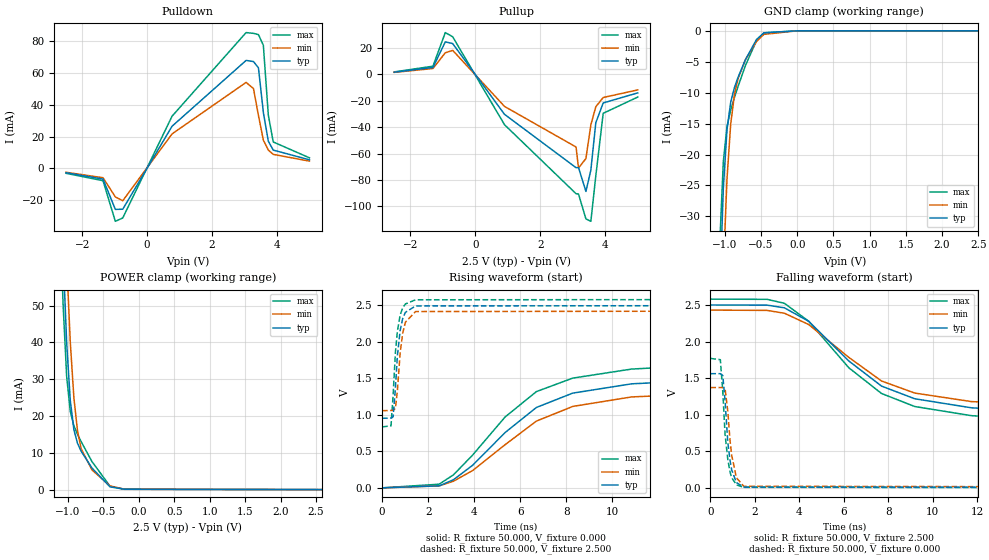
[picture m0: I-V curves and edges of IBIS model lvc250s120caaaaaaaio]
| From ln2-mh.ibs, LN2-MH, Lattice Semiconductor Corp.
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|   Model lvc250s120caaaaaaaio
[Model] lvc250s120caaaaaaaio
Model_type I/O
Polarity   Non-Inverting
Enable   Active-Low
Vinl =  0.700V
Vinh =  1.700V
Vmeas =  1.250V
Cref =  0.0F
Rref =  1.000M
Vref =  0.0V
C_comp   2.000pF   1.500pF   2.500pF
[Temperature Range]   25.000   0.125k   -40.000
[Voltage Range]   2.500V   2.430V   2.580V
[C Comp Corner]
C_comp   2.000pF   1.500pF   2.500pF
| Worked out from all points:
|   slope of the pulldown table from 0 to 0.375 V, typ, clamps not added: 26.1 ohm
|   slope of the pullup table from 0 to 0.375 V, typ, clamps not added: 25.9 ohm
|   GND clamp passes 1 mA (typ) near -0.53 V on its own axis
|   POWER clamp passes 1 mA (typ) near -0.43 V on its own axis
|   rising waveform, R_fixture 50.000, V_fixture 0.000: 20-80 % time 3.81ns typ, 3.97ns min, 3.68ns max; typ from 0 V to 1.56 V
|   rising waveform, R_fixture 50.000, V_fixture 2.500: 20-80 % time 245ps typ, 254ps min, 237ps max; typ from 0.951 V to 2.5 V
|   falling waveform, R_fixture 50.000, V_fixture 2.500: 20-80 % time 3.93ns typ, 3.98ns min, 3.86ns max; typ from 2.5 V to 0.951 V
|   falling waveform, R_fixture 50.000, V_fixture 0.000: 20-80 % time 272ps typ, 284ps min, 263ps max; typ from 1.56 V to 0 V
[Pulldown]
|Voltage   I(typ)   I(min)   I(max)
-2.5V     -2.708mA   -2.448mA   -3.091mA
-1.36V    -6.732mA   -5.86mA    -7.74mA
-980mV    -25.78mA   -17.94mA   -33.28mA
-752mV    -25.68mA   -20.35mA   -31.19mA
768mV     26.55mA    21.72mA    32.86mA
3.048V    67.93mA    54.1mA     85.45mA
3.276V    67.21mA    50.18mA    84.96mA
3.428V    63.3mA     33.26mA    84.17mA
3.58V     35.14mA    17.71mA    77.42mA
3.732V    17.13mA    11.54mA    33.55mA
3.884V    11.51mA    8.819mA    16.63mA
5V        5.405mA    4.565mA    6.644mA
[Pullup]
|Voltage   I(typ)   I(min)   I(max)
-2.5V     1.551mA    1.435mA    1.806mA
-1.308V   5.158mA    4.339mA    6.103mA
-928mV    24.52mA    16.25mA    31.54mA
-700mV    23.2mA     18.08mA    28.32mA
896mV     -30.3mA    -24.31mA   -38.15mA
3.1V      -70.65mA   -55.01mA   -90.32mA
3.176V    -70.61mA   -70.87mA   -90.58mA
3.404V    -88.6mA    -63.74mA   -109.4mA
3.556V    -72.51mA   -38.29mA   -111.2mA
3.708V    -36.7mA    -24.59mA   -76.98mA
3.936V    -21.7mA    -17.57mA   -29.52mA
5V        -14.08mA   -11.83mA   -17.25mA
[GND_clamp]
|Voltage   I(typ)   I(min)   I(max)
-2.5V     -1.176A    -1.175A    -1.18A
-1.072V   -43.15mA   -59.89mA   -34.87mA
-1.021V   -25.5mA    -38.75mA   -21.15mA
-970mV    -15.94mA   -23.91mA   -15.48mA
-919mV    -11.55mA   -15.09mA   -12.8mA
-868mV    -9.208mA   -10.36mA   -10.81mA
-817mV    -7.507mA   -7.725mA   -8.99mA
-715mV    -4.652mA   -4.658mA   -5.6mA
-562mV    -1.396mA   -1.715mA   -1.585mA
-460mV    -331.3uA   -573.9uA   -320.1uA
-1mV      -317.6nA   -575.7nA   -335.3nA
2.5V      0A         0A         0A
[POWER_clamp]
|Voltage   I(typ)   I(min)   I(max)
-2.498V   1.294A     1.303A     1.292A
-1.121V   95.13mA    121.6mA    80.05mA
-1.07V    64.32mA    89.7mA     50.73mA
-1.019V   40.01mA    62.11mA    30.82mA
-968mV    24.28mA    40.2mA     21.28mA
-917mV    16.32mA    25mA       17.36mA
-866mV    12.61mA    15.98mA    15.04mA
-815mV    10.46mA    11.14mA    13.07mA
-662mV    5.878mA    5.353mA    7.63mA
-407mV    756.4uA    1.004mA    934.2uA
-203mV    93.32uA    107.9uA    92.71uA
2.58V     0A         0A         0A
[Ramp]
| variable   typ   min   max
dV/dt_r   0.959/3.821n   0.842/3.981n   1.086/3.678n
dV/dt_f   0.952/3.925n   0.845/3.979n   1.072/3.863n
R_load = 50.000
[Rising Waveform]
R_fixture = 50.000
V_fixture = 0.000
V_fixture_min = 0.000
V_fixture_max = 0.000
|  time   V(typ)   V(min)   V(max)
0s        32.67uV    -14.14uV   8.614uV
2.478ns   27.6mV     27.1mV     50.15mV
3.098ns   111.4mV    90.83mV    178.2mV
3.928ns   308.5mV    236.5mV    447.9mV
5.338ns   755.8mV    589.7mV    968.8mV
6.697ns   1.099V     912.4mV    1.316V
8.273ns   1.295V     1.113V     1.5V
10.83ns   1.422V     1.243V     1.624V
18.84ns   1.546V     1.353V     1.757V
50ns      1.561V     1.371V     1.77V
[Rising Waveform]
R_fixture = 50.000
V_fixture = 2.500
V_fixture_min = 2.430
V_fixture_max = 2.580
|  time   V(typ)   V(min)   V(max)
0s        950.8mV    1.055V     833.1mV
387ps     954.5mV    1.058V     848mV
479ps     971.4mV    1.06V      1.268V
581ps     1.377V     1.088V     1.865V
663ps     1.801V     1.328V     2.137V
783ps     2.151V     1.838V     2.363V
892ps     2.312V     2.111V     2.459V
1.012ns   2.399V     2.265V     2.514V
1.453ns   2.487V     2.41V      2.571V
50ns      2.5V       2.43V      2.58V
[Falling Waveform]
R_fixture = 50.000
V_fixture = 2.500
V_fixture_min = 2.430
V_fixture_max = 2.580
|  time   V(typ)   V(min)   V(max)
0s        2.5V       2.43V      2.58V
2.556ns   2.498V     2.426V     2.577V
3.334ns   2.461V     2.387V     2.523V
4.426ns   2.277V     2.233V     2.278V
6.235ns   1.734V     1.783V     1.641V
7.706ns   1.391V     1.461V     1.29V
9.2ns     1.218V     1.296V     1.112V
11.76ns   1.094V     1.179V     986.6mV
20.08ns   964.1mV    1.073V     842.9mV
50ns      950.8mV    1.055V     833.1mV
[Falling Waveform]
R_fixture = 50.000
V_fixture = 0.000
V_fixture_min = 0.000
V_fixture_max = 0.000
|  time   V(typ)   V(min)   V(max)
0s        1.561V     1.371V     1.77V
449ps     1.561V     1.371V     1.752V
560ps     1.535V     1.371V     1.313V
663ps     1.186V     1.357V     727.5mV
786ps     619.3mV    1.043V     387.5mV
886ps     373.7mV    645.5mV    216.6mV
959ps     247.5mV    448.5mV    140.8mV
1.174ns   71.79mV    137.5mV    40.91mV
1.507ns   11.67mV    21.79mV    6.941mV
50ns      32.67uV    -14.14uV   8.614uV
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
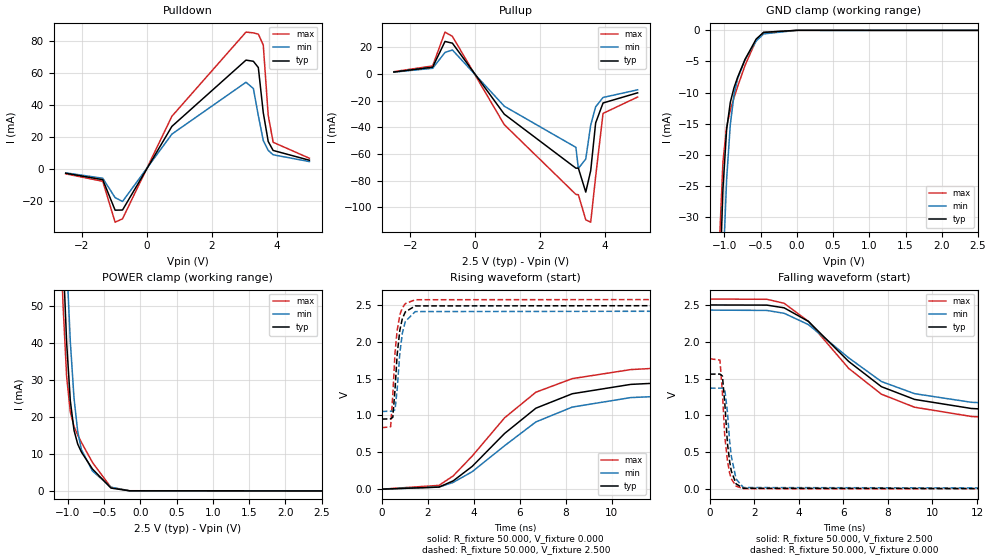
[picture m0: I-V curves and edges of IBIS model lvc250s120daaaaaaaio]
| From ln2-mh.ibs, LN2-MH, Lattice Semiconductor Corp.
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|   Model lvc250s120daaaaaaaio
[Model] lvc250s120daaaaaaaio
Model_type I/O
Polarity   Non-Inverting
Enable   Active-Low
Vinl =  0.700V
Vinh =  1.700V
Vmeas =  1.250V
Cref =  0.0F
Rref =  1.000M
Vref =  0.0V
C_comp   2.000pF   1.500pF   2.500pF
[Temperature Range]   25.000   0.125k   -40.000
[Voltage Range]   2.500V   2.430V   2.580V
[C Comp Corner]
C_comp   2.000pF   1.500pF   2.500pF
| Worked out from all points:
|   slope of the pulldown table from 0 to 0.375 V, typ, clamps not added: 26.1 ohm
|   slope of the pullup table from 0 to 0.375 V, typ, clamps not added: 26 ohm
|   GND clamp passes 1 mA (typ) near -0.53 V on its own axis
|   POWER clamp passes 1 mA (typ) near -0.42 V on its own axis
|   rising waveform, R_fixture 50.000, V_fixture 0.000: 20-80 % time 3.81ns typ, 3.97ns min, 3.68ns max; typ from 0 V to 1.56 V
|   rising waveform, R_fixture 50.000, V_fixture 2.500: 20-80 % time 245ps typ, 254ps min, 237ps max; typ from 0.951 V to 2.5 V
|   falling waveform, R_fixture 50.000, V_fixture 2.500: 20-80 % time 3.93ns typ, 3.98ns min, 3.86ns max; typ from 2.5 V to 0.951 V
|   falling waveform, R_fixture 50.000, V_fixture 0.000: 20-80 % time 272ps typ, 283ps min, 263ps max; typ from 1.56 V to 0 V
[Pulldown]
|Voltage   I(typ)   I(min)   I(max)
-2.5V     -2.708mA   -2.448mA   -3.091mA
-1.36V    -6.732mA   -5.86mA    -7.74mA
-980mV    -25.78mA   -17.94mA   -33.28mA
-752mV    -25.68mA   -20.35mA   -31.19mA
768mV     26.55mA    21.72mA    32.86mA
3.048V    67.91mA    54.09mA    85.42mA
3.276V    67.19mA    50.17mA    84.93mA
3.428V    63.28mA    33.25mA    84.14mA
3.58V     35.13mA    17.7mA     77.39mA
3.732V    17.13mA    11.54mA    33.54mA
3.884V    11.51mA    8.816mA    16.62mA
5V        5.403mA    4.564mA    6.641mA
[Pullup]
|Voltage   I(typ)   I(min)   I(max)
-2.5V     1.549mA    1.434mA    1.804mA
-1.308V   5.154mA    4.335mA    6.097mA
-928mV    24.49mA    16.24mA    31.51mA
-700mV    23.18mA    18.06mA    28.28mA
896mV     -30.11mA   -24.12mA   -37.97mA
3.1V      -70.65mA   -55.01mA   -90.32mA
3.176V    -70.61mA   -70.87mA   -90.58mA
3.404V    -88.6mA    -63.74mA   -109.4mA
3.556V    -72.51mA   -38.29mA   -111.2mA
3.708V    -36.7mA    -24.59mA   -76.98mA
3.936V    -21.7mA    -17.57mA   -29.52mA
5V        -14.08mA   -11.83mA   -17.25mA
[GND_clamp]
|Voltage   I(typ)   I(min)   I(max)
-2.5V     -1.176A    -1.175A    -1.18A
-1.072V   -43.15mA   -59.89mA   -34.87mA
-1.021V   -25.5mA    -38.75mA   -21.15mA
-970mV    -15.94mA   -23.91mA   -15.48mA
-919mV    -11.55mA   -15.09mA   -12.8mA
-868mV    -9.208mA   -10.36mA   -10.81mA
-817mV    -7.507mA   -7.725mA   -8.99mA
-715mV    -4.652mA   -4.658mA   -5.6mA
-562mV    -1.396mA   -1.715mA   -1.585mA
-460mV    -331.3uA   -573.9uA   -320.1uA
-1mV      -317.6nA   -575.7nA   -335.3nA
2.5V      19.47nA    0A         -24.11uA
[POWER_clamp]
|Voltage   I(typ)   I(min)   I(max)
-2.498V   1.294A     1.303A     1.292A
-1.121V   95.14mA    121.6mA    80.07mA
-1.07V    64.33mA    89.71mA    50.75mA
-1.019V   40.02mA    62.12mA    30.84mA
-968mV    24.3mA     40.21mA    21.31mA
-917mV    16.34mA    25.01mA    17.39mA
-866mV    12.64mA    16mA       15.07mA
-815mV    10.49mA    11.15mA    13.11mA
-662mV    5.902mA    5.367mA    7.663mA
-407mV    768.2uA    1.002mA    960.5uA
-152mV    40.9uA     39.04uA    48.9uA
2.5V      0A         0A         24.96uA
[Ramp]
| variable   typ   min   max
dV/dt_r   0.959/3.821n   0.842/3.984n   1.086/3.681n
dV/dt_f   0.952/3.927n   0.845/3.979n   1.072/3.860n
R_load = 50.000
[Rising Waveform]
R_fixture = 50.000
V_fixture = 0.000
V_fixture_min = 0.000
V_fixture_max = 0.000
|  time   V(typ)   V(min)   V(max)
0s        32.67uV    -14.14uV   8.614uV
2.487ns   28.4mV     27.74mV    51.43mV
3.104ns   112.5mV    91.65mV    179.8mV
3.933ns   309.9mV    237.6mV    449.8mV
5.338ns   755.8mV    589.7mV    968.7mV
6.698ns   1.099V     912.6mV    1.316V
8.278ns   1.295V     1.114V     1.5V
10.82ns   1.422V     1.243V     1.623V
18.84ns   1.546V     1.353V     1.757V
50ns      1.561V     1.371V     1.77V
[Rising Waveform]
R_fixture = 50.000
V_fixture = 2.500
V_fixture_min = 2.430
V_fixture_max = 2.580
|  time   V(typ)   V(min)   V(max)
0s        950.8mV    1.055V     833.1mV
387ps     954.5mV    1.058V     848mV
481ps     975.1mV    1.06V      1.282V
577ps     1.354V     1.08V      1.849V
668ps     1.82V      1.346V     2.15V
787ps     2.159V     1.85V      2.368V
897ps     2.317V     2.12V      2.462V
1.026ns   2.406V     2.276V     2.518V
1.456ns   2.487V     2.41V      2.571V
50ns      2.5V       2.43V      2.58V
[Falling Waveform]
R_fixture = 50.000
V_fixture = 2.500
V_fixture_min = 2.430
V_fixture_max = 2.580
|  time   V(typ)   V(min)   V(max)
0s        2.5V       2.43V      2.58V
2.556ns   2.498V     2.426V     2.577V
3.334ns   2.461V     2.387V     2.523V
4.426ns   2.277V     2.233V     2.277V
6.236ns   1.733V     1.782V     1.639V
7.705ns   1.391V     1.461V     1.289V
9.197ns   1.218V     1.296V     1.112V
11.75ns   1.095V     1.179V     986.7mV
20.09ns   964mV      1.073V     842.8mV
50ns      950.8mV    1.055V     833.1mV
[Falling Waveform]
R_fixture = 50.000
V_fixture = 0.000
V_fixture_min = 0.000
V_fixture_max = 0.000
|  time   V(typ)   V(min)   V(max)
0s        1.561V     1.371V     1.77V
449ps     1.562V     1.371V     1.752V
560ps     1.535V     1.371V     1.313V
666ps     1.172V     1.354V     715.9mV
786ps     618.9mV    1.043V     387.5mV
886ps     373.5mV    645.5mV    216.7mV
959ps     247.4mV    448.5mV    140.8mV
1.174ns   71.75mV    137.5mV    40.9mV
1.506ns   11.72mV    21.91mV    6.975mV
50ns      32.67uV    -14.14uV   8.614uV
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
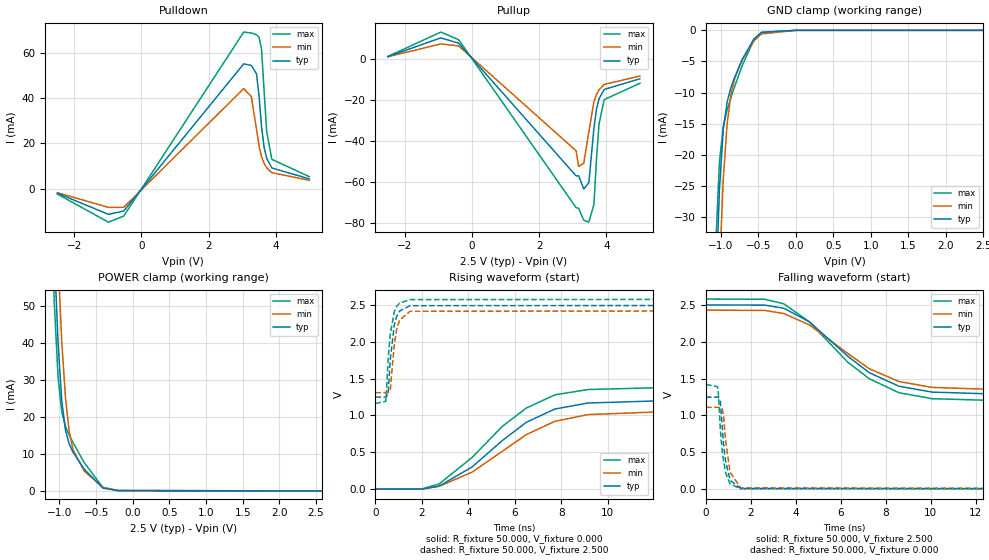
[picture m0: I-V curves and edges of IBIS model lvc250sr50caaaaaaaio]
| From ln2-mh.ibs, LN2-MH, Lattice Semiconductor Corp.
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|   Model lvc250sr50caaaaaaaio
[Model] lvc250sr50caaaaaaaio
Model_type I/O
Polarity   Non-Inverting
Enable   Active-Low
Vinl =  0.700V
Vinh =  1.700V
Vmeas =  1.250V
Cref =  0.0F
Rref =  1.000M
Vref =  0.0V
C_comp   2.000pF   1.500pF   2.500pF
[Temperature Range]   25.000   0.125k   -40.000
[Voltage Range]   2.500V   2.430V   2.580V
[C Comp Corner]
C_comp   2.000pF   1.500pF   2.500pF
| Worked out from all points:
|   slope of the pulldown table from 0 to 0.375 V, typ, clamps not added: 50.2 ohm
|   slope of the pullup table from 0 to 0.375 V, typ, clamps not added: 49.7 ohm
|   GND clamp passes 1 mA (typ) near -0.53 V on its own axis
|   POWER clamp passes 1 mA (typ) near -0.43 V on its own axis
|   rising waveform, R_fixture 50.000, V_fixture 0.000: 20-80 % time 3.07ns typ, 3.33ns min, 3.01ns max; typ from 0 V to 1.25 V
|   rising waveform, R_fixture 50.000, V_fixture 2.500: 20-80 % time 239ps typ, 247ps min, 232ps max; typ from 1.25 V to 2.5 V
|   falling waveform, R_fixture 50.000, V_fixture 2.500: 20-80 % time 3.04ns typ, 3.19ns min, 3.04ns max; typ from 2.5 V to 1.25 V
|   falling waveform, R_fixture 50.000, V_fixture 0.000: 20-80 % time 255ps typ, 265ps min, 250ps max; typ from 1.25 V to 0 V
[Pulldown]
|Voltage   I(typ)   I(min)   I(max)
-2.5V     -2.064mA   -1.818mA   -2.433mA
-980mV    -11.4mA    -8.318mA   -14.87mA
-524mV    -9.937mA   -8.28mA    -12.15mA
3.048V    55.11mA    44.17mA    69.14mA
3.276V    54.4mA     40.56mA    68.73mA
3.428V    50.72mA    26.29mA    67.91mA
3.504V    40.94mA    18.78mA    66.89mA
3.58V     27.11mA    14mA       61.39mA
3.656V    18.12mA    11.09mA    42.87mA
3.732V    13.4mA     9.163mA    25.24mA
3.884V    9.09mA     7.016mA    12.92mA
5V        4.273mA    3.632mA    5.256mA
[Pullup]
|Voltage   I(typ)   I(min)   I(max)
-2.5V     1.035mA    952.2uA    1.127mA
-928mV    10.1mA     7.158mA    12.91mA
-396mV    7.524mA    6.191mA    9.211mA
3.1V      -56.91mA   -44.73mA   -72.32mA
3.176V    -56.89mA   -52.29mA   -72.61mA
3.328V    -63.3mA    -50.81mA   -78.42mA
3.48V     -60.25mA   -35.45mA   -79.4mA
3.632V    -33.64mA   -20.82mA   -70.66mA
3.708V    -24.4mA    -17.33mA   -48.52mA
3.784V    -19.45mA   -15.11mA   -31.55mA
3.936V    -14.94mA   -12.52mA   -19.88mA
5V        -9.779mA   -8.442mA   -11.94mA
[GND_clamp]
|Voltage   I(typ)   I(min)   I(max)
-2.5V     -1.176A    -1.175A    -1.18A
-1.072V   -43.15mA   -59.89mA   -34.87mA
-1.021V   -25.5mA    -38.75mA   -21.15mA
-970mV    -15.94mA   -23.91mA   -15.48mA
-919mV    -11.55mA   -15.09mA   -12.8mA
-868mV    -9.208mA   -10.36mA   -10.81mA
-817mV    -7.507mA   -7.725mA   -8.99mA
-715mV    -4.652mA   -4.658mA   -5.6mA
-562mV    -1.396mA   -1.715mA   -1.585mA
-460mV    -331.3uA   -573.9uA   -320.1uA
-1mV      -317.6nA   -575.7nA   -335.3nA
2.5V      0A         0A         0A
[POWER_clamp]
|Voltage   I(typ)   I(min)   I(max)
-2.498V   1.294A     1.303A     1.292A
-1.121V   95.13mA    121.6mA    80.05mA
-1.07V    64.32mA    89.7mA     50.73mA
-1.019V   40.01mA    62.11mA    30.82mA
-968mV    24.28mA    40.2mA     21.28mA
-917mV    16.32mA    25mA       17.36mA
-866mV    12.61mA    15.98mA    15.04mA
-815mV    10.46mA    11.14mA    13.07mA
-662mV    5.878mA    5.353mA    7.63mA
-407mV    756.4uA    1.004mA    934.2uA
-203mV    93.32uA    107.9uA    92.71uA
2.58V     0A         0A         0A
[Ramp]
| variable   typ   min   max
dV/dt_r   0.765/3.076n   0.681/3.352n   0.870/3.013n
dV/dt_f   0.765/3.045n   0.687/3.206n   0.868/3.042n
R_load = 50.000
[Rising Waveform]
R_fixture = 50.000
V_fixture = 0.000
V_fixture_min = 0.000
V_fixture_max = 0.000
|  time   V(typ)   V(min)   V(max)
0s        7.351uV    -59.76uV   -25.03uV
2.023ns   1.791mV    3.143mV    4.547mV
2.752ns   42.69mV    38.47mV    72.34mV
4.17ns    302.6mV    232.2mV    431.9mV
5.472ns   661.4mV    515.1mV    853.5mV
6.502ns   907.3mV    740.5mV    1.101V
7.731ns   1.088V     921mV      1.28V
9.154ns   1.169V     1.012V     1.352V
16.71ns   1.242V     1.103V     1.415V
50ns      1.249V     1.111V     1.421V
[Rising Waveform]
R_fixture = 50.000
V_fixture = 2.500
V_fixture_min = 2.430
V_fixture_max = 2.580
|  time   V(typ)   V(min)   V(max)
0s        1.25V      1.309V     1.163V
442ps     1.25V      1.31V      1.192V
471ps     1.249V     1.31V      1.297V
550ps     1.315V     1.309V     1.772V
642ps     1.761V     1.352V     2.107V
810ps     2.222V     1.952V     2.404V
912ps     2.342V     2.164V     2.477V
1.036ns   2.416V     2.293V     2.524V
1.492ns   2.49V      2.414V     2.573V
50ns      2.5V       2.43V      2.58V
[Falling Waveform]
R_fixture = 50.000
V_fixture = 2.500
V_fixture_min = 2.430
V_fixture_max = 2.580
|  time   V(typ)   V(min)   V(max)
0s        2.5V       2.43V      2.58V
2.61ns    2.498V     2.426V     2.577V
3.458ns   2.456V     2.384V     2.516V
4.6ns     2.271V     2.229V     2.27V
6.303ns   1.805V     1.843V     1.724V
7.261ns   1.581V     1.635V     1.499V
8.582ns   1.397V     1.461V     1.309V
10.06ns   1.317V     1.381V     1.228V
16.53ns   1.257V     1.316V     1.17V
50ns      1.25V      1.309V     1.163V
[Falling Waveform]
R_fixture = 50.000
V_fixture = 0.000
V_fixture_min = 0.000
V_fixture_max = 0.000
|  time   V(typ)   V(min)   V(max)
0s        1.249V     1.111V     1.421V
512ps     1.249V     1.111V     1.391V
552ps     1.249V     1.111V     1.288V
640ps     1.185V     1.112V     795.9mV
721ps     845.3mV    1.089V     517.3mV
781ps     604.5mV    992.8mV    377.4mV
871ps     380.2mV    661.1mV    223.3mV
1.071ns   120.7mV    230.1mV    69.48mV
1.541ns   9.082mV    16.9mV     5.451mV
50ns      7.351uV    -59.76uV   -25.03uV
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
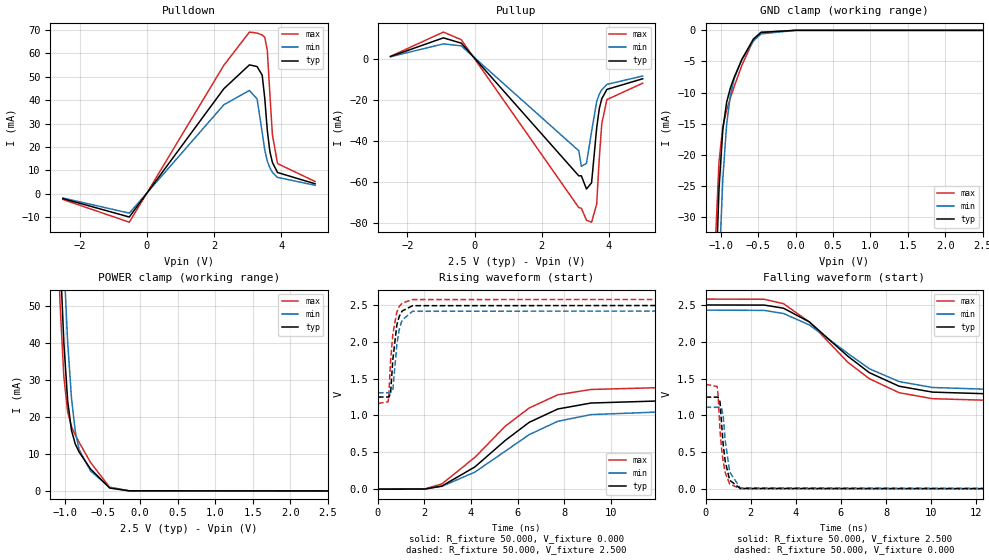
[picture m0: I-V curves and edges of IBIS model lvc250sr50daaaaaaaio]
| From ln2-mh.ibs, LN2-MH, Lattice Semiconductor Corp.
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|   Model lvc250sr50daaaaaaaio
[Model] lvc250sr50daaaaaaaio
Model_type I/O
Polarity   Non-Inverting
Enable   Active-Low
Vinl =  0.700V
Vinh =  1.700V
Vmeas =  1.250V
Cref =  0.0F
Rref =  1.000M
Vref =  0.0V
C_comp   2.000pF   1.500pF   2.500pF
[Temperature Range]   25.000   0.125k   -40.000
[Voltage Range]   2.500V   2.430V   2.580V
[C Comp Corner]
C_comp   2.000pF   1.500pF   2.500pF
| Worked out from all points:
|   slope of the pulldown table from 0 to 0.375 V, typ, clamps not added: 50.2 ohm
|   slope of the pullup table from 0 to 0.375 V, typ, clamps not added: 50.2 ohm
|   GND clamp passes 1 mA (typ) near -0.53 V on its own axis
|   POWER clamp passes 1 mA (typ) near -0.42 V on its own axis
|   rising waveform, R_fixture 50.000, V_fixture 0.000: 20-80 % time 3.07ns typ, 3.33ns min, 3.01ns max; typ from 0 V to 1.25 V
|   rising waveform, R_fixture 50.000, V_fixture 2.500: 20-80 % time 238ps typ, 247ps min, 232ps max; typ from 1.25 V to 2.5 V
|   falling waveform, R_fixture 50.000, V_fixture 2.500: 20-80 % time 3.04ns typ, 3.19ns min, 3.04ns max; typ from 2.5 V to 1.25 V
|   falling waveform, R_fixture 50.000, V_fixture 0.000: 20-80 % time 255ps typ, 265ps min, 250ps max; typ from 1.25 V to 0 V
[Pulldown]
|Voltage   I(typ)   I(min)   I(max)
-2.5V     -2.064mA   -1.818mA   -2.433mA
-524mV    -9.937mA   -8.28mA    -12.15mA
2.288V    44.9mA     38.05mA    54.93mA
3.048V    55.09mA    44.16mA    69.11mA
3.276V    54.38mA    40.54mA    68.7mA
3.428V    50.7mA     26.28mA    67.88mA
3.504V    40.92mA    18.77mA    66.85mA
3.58V     27.1mA     13.99mA    61.36mA
3.656V    18.12mA    11.09mA    42.86mA
3.732V    13.4mA     9.159mA    25.23mA
3.884V    9.086mA    7.013mA    12.91mA
5V        4.27mA     3.63mA     5.253mA
[Pullup]
|Voltage   I(typ)   I(min)   I(max)
-2.5V     1.032mA    950.4uA    1.125mA
-928mV    10.08mA    7.144mA    12.88mA
-396mV    7.514mA    6.194mA    9.185mA
3.1V      -56.91mA   -44.73mA   -72.32mA
3.176V    -56.89mA   -52.29mA   -72.61mA
3.328V    -63.3mA    -50.81mA   -78.42mA
3.48V     -60.25mA   -35.45mA   -79.4mA
3.632V    -33.64mA   -20.82mA   -70.66mA
3.708V    -24.4mA    -17.33mA   -48.52mA
3.784V    -19.45mA   -15.11mA   -31.55mA
3.936V    -14.94mA   -12.52mA   -19.88mA
5V        -9.779mA   -8.442mA   -11.94mA
[GND_clamp]
|Voltage   I(typ)   I(min)   I(max)
-2.5V     -1.176A    -1.175A    -1.18A
-1.072V   -43.15mA   -59.89mA   -34.87mA
-1.021V   -25.5mA    -38.75mA   -21.15mA
-970mV    -15.94mA   -23.91mA   -15.48mA
-919mV    -11.55mA   -15.09mA   -12.8mA
-868mV    -9.208mA   -10.36mA   -10.81mA
-817mV    -7.507mA   -7.725mA   -8.99mA
-715mV    -4.652mA   -4.658mA   -5.6mA
-562mV    -1.396mA   -1.715mA   -1.585mA
-460mV    -331.3uA   -573.9uA   -320.1uA
-1mV      -317.6nA   -575.7nA   -335.3nA
2.5V      19.47nA    0A         -24.11uA
[POWER_clamp]
|Voltage   I(typ)   I(min)   I(max)
-2.498V   1.294A     1.303A     1.292A
-1.121V   95.14mA    121.6mA    80.07mA
-1.07V    64.33mA    89.71mA    50.75mA
-1.019V   40.02mA    62.12mA    30.84mA
-968mV    24.3mA     40.21mA    21.31mA
-917mV    16.34mA    25.01mA    17.39mA
-866mV    12.64mA    16mA       15.07mA
-815mV    10.49mA    11.15mA    13.11mA
-662mV    5.902mA    5.367mA    7.663mA
-407mV    768.2uA    1.002mA    960.5uA
-152mV    40.9uA     39.04uA    48.9uA
2.5V      0A         0A         24.96uA
[Ramp]
| variable   typ   min   max
dV/dt_r   0.765/3.075n   0.681/3.341n   0.870/3.014n
dV/dt_f   0.765/3.051n   0.687/3.218n   0.868/3.049n
R_load = 50.000
[Rising Waveform]
R_fixture = 50.000
V_fixture = 0.000
V_fixture_min = 0.000
V_fixture_max = 0.000
|  time   V(typ)   V(min)   V(max)
0s        7.351uV    -59.76uV   -25.03uV
2.023ns   1.791mV    3.142mV    4.552mV
2.752ns   42.69mV    38.46mV    72.42mV
4.17ns    302.6mV    232.2mV    432.4mV
5.472ns   661.4mV    515.1mV    854.5mV
6.502ns   907.3mV    740.5mV    1.102V
7.731ns   1.088V     921mV      1.281V
9.156ns   1.169V     1.012V     1.353V
16.71ns   1.242V     1.103V     1.417V
50ns      1.249V     1.111V     1.423V
[Rising Waveform]
R_fixture = 50.000
V_fixture = 2.500
V_fixture_min = 2.430
V_fixture_max = 2.580
|  time   V(typ)   V(min)   V(max)
0s        1.25V      1.308V     1.163V
438ps     1.251V     1.309V     1.186V
468ps     1.249V     1.309V     1.28V
543ps     1.298V     1.308V     1.737V
642ps     1.761V     1.351V     2.107V
813ps     2.227V     1.96V      2.406V
912ps     2.342V     2.164V     2.477V
1.04ns    2.418V     2.296V     2.525V
1.49ns    2.49V      2.414V     2.573V
50ns      2.5V       2.43V      2.58V
[Falling Waveform]
R_fixture = 50.000
V_fixture = 2.500
V_fixture_min = 2.430
V_fixture_max = 2.580
|  time   V(typ)   V(min)   V(max)
0s        2.5V       2.43V      2.58V
2.61ns    2.498V     2.426V     2.577V
3.454ns   2.456V     2.384V     2.517V
4.601ns   2.27V      2.229V     2.27V
6.304ns   1.805V     1.843V     1.723V
7.261ns   1.581V     1.634V     1.499V
8.582ns   1.397V     1.46V      1.309V
10.06ns   1.317V     1.38V      1.228V
16.52ns   1.257V     1.316V     1.17V
50ns      1.25V      1.308V     1.163V
[Falling Waveform]
R_fixture = 50.000
V_fixture = 0.000
V_fixture_min = 0.000
V_fixture_max = 0.000
|  time   V(typ)   V(min)   V(max)
0s        1.249V     1.111V     1.423V
511ps     1.249V     1.111V     1.394V
551ps     1.249V     1.111V     1.294V
639ps     1.187V     1.112V     801.4mV
721ps     845.3mV    1.089V     518mV
781ps     604.5mV    992.8mV    377.8mV
872ps     378.1mV    657.7mV    222.3mV
1.07ns    121.4mV    231.4mV    69.96mV
1.537ns   9.271mV    17.27mV    5.565mV
50ns      7.351uV    -59.76uV   -25.03uV
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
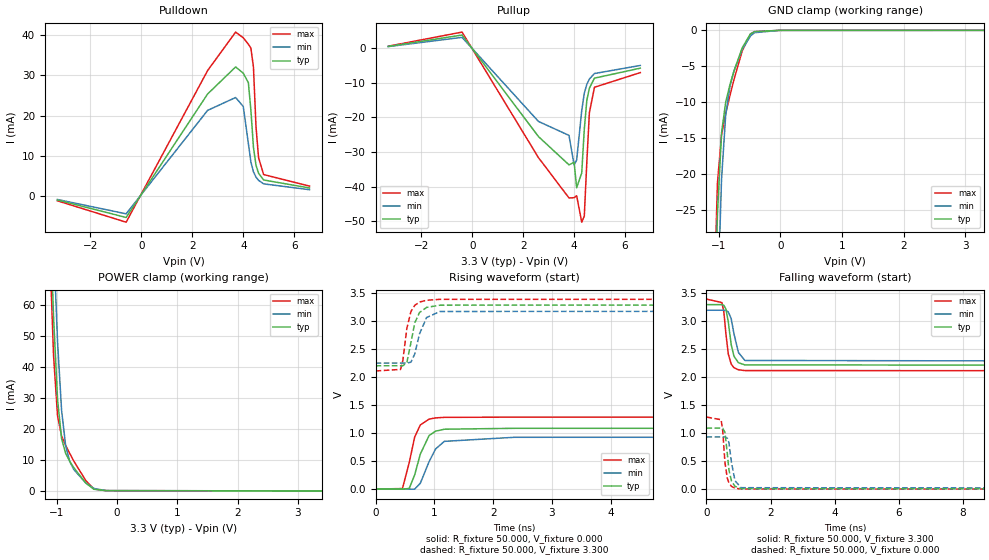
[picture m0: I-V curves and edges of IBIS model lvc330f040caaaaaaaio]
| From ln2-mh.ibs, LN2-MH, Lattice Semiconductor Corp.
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|   Model lvc330f040caaaaaaaio
[Model] lvc330f040caaaaaaaio
Model_type I/O
Polarity   Non-Inverting
Enable   Active-Low
Vinl =  0.800V
Vinh =  2.000V
Vmeas =  1.650V
Cref =  0.0F
Rref =  1.000M
Vref =  0.0V
C_comp   2.000pF   1.500pF   2.500pF
[Temperature Range]   25.000   0.125k   -40.000
[Voltage Range]   3.300V   3.200V   3.400V
[C Comp Corner]
C_comp   2.000pF   1.500pF   2.500pF
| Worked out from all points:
|   slope of the pulldown table from 0 to 0.495 V, typ, clamps not added: 100 ohm
|   slope of the pullup table from 0 to 0.495 V, typ, clamps not added: 98.9 ohm
|   GND clamp passes 1 mA (typ) near -0.53 V on its own axis
|   POWER clamp passes 1 mA (typ) near -0.42 V on its own axis
|   rising waveform, R_fixture 50.000, V_fixture 0.000: 20-80 % time 196ps typ, 247ps min, 167ps max; typ from 0 V to 1.09 V
|   rising waveform, R_fixture 50.000, V_fixture 3.300: 20-80 % time 133ps typ, 155ps min, 115ps max; typ from 2.21 V to 3.3 V
|   falling waveform, R_fixture 50.000, V_fixture 3.300: 20-80 % time 171ps typ, 212ps min, 149ps max; typ from 3.3 V to 2.21 V
|   falling waveform, R_fixture 50.000, V_fixture 0.000: 20-80 % time 127ps typ, 140ps min, 117ps max; typ from 1.09 V to 0 V
[Pulldown]
|Voltage   I(typ)   I(min)   I(max)
-3.3V     -985.1uA   -853.1uA   -1.176mA
-600mV    -5.328mA   -4.426mA   -6.507mA
2.6V      25.4mA     21.32mA    31.23mA
3.7V      32.13mA    24.52mA    40.8mA
4V        30.57mA    22.28mA    39.37mA
4.2V      28.22mA    13.07mA    37.8mA
4.3V      21.3mA     8.466mA    36.79mA
4.4V      12.1mA     6.031mA    32.07mA
4.5V      7.678mA    4.706mA    17.26mA
4.6V      5.684mA    3.905mA    9.549mA
4.8V      3.996mA    3.032mA    5.349mA
6.6V      2.007mA    1.58mA     2.473mA
[Pullup]
|Voltage   I(typ)   I(min)   I(max)
-3.3V     467.2uA    421.2uA    537uA
-400mV    3.762mA    3.089mA    4.612mA
2.6V      -25.54mA   -21.17mA   -31.62mA
3.8V      -33.71mA   -25.21mA   -43.26mA
4V        -32.94mA   -33.73mA   -43.17mA
4.1V      -40.33mA   -32.32mA   -42.61mA
4.3V      -36.01mA   -18.03mA   -50.25mA
4.4V      -23.41mA   -13.04mA   -48.5mA
4.5V      -15.08mA   -10.45mA   -32.83mA
4.6V      -11.57mA   -8.921mA   -18.66mA
4.8V      -8.681mA   -7.343mA   -11.31mA
6.6V      -5.798mA   -5.016mA   -7.082mA
[GND_clamp]
|Voltage   I(typ)   I(min)   I(max)
-3.3V     -1.861A    -1.855A    -1.868A
-1.089V   -50.83mA   -68.22mA   -41.81mA
-1.022V   -25.77mA   -39.11mA   -21.36mA
-955mV    -14.31mA   -20.77mA   -14.6mA
-888mV    -10.03mA   -11.88mA   -11.61mA
-821mV    -7.659mA   -7.903mA   -9.179mA
-754mV    -5.715mA   -5.674mA   -6.892mA
-620mV    -2.446mA   -2.677mA   -2.886mA
-486mV    -500.9uA   -793.7uA   -505.5uA
-419mV    -184.7uA   -329.9uA   -181.9uA
-17mV     -4.77uA    -4.625uA   -5.541uA
3.3V      0A         0A         0A
[POWER_clamp]
|Voltage   I(typ)   I(min)   I(max)
-3.266V   2.002A     2.005A     2.003A
-1.122V   95.84mA    122.3mA    80.75mA
-1.055V   56.43mA    81.13mA    43.84mA
-988mV    29.47mA    48.06mA    24.16mA
-921mV    16.85mA    26mA       17.72mA
-854mV    12.14mA    14.62mA    14.69mA
-787mV    9.602mA    9.553mA    12.13mA
-720mV    7.548mA    6.952mA    9.693mA
-519mV    2.524mA    2.533mA    3.308mA
-385mV    541.5uA    790.3uA    641.3uA
-184mV    92.6uA     101.7uA    92.48uA
3.4V      0A         0A         0A
[Ramp]
| variable   typ   min   max
dV/dt_r   0.669/0.196n   0.572/0.247n   0.790/0.168n
dV/dt_f   0.670/0.172n   0.580/0.213n   0.788/0.150n
R_load = 50.000
[Rising Waveform]
R_fixture = 50.000
V_fixture = 0.000
V_fixture_min = 0.000
V_fixture_max = 0.000
|  time   V(typ)   V(min)   V(max)
0s        117uV      -10.83uV   49.78uV
457ps     -981.8uV   -283.3uV   8.963mV
572ps     10.2mV     -1.891mV   472mV
665ps     252.1mV    -1.835mV   929.6mV
761ps     625.2mV    104.2mV    1.147V
911ps     958.5mV    490.5mV    1.252V
1.022ns   1.036V     718.6mV    1.274V
1.171ns   1.071V     853.8mV    1.283V
2.361ns   1.087V     926.4mV    1.287V
50ns      1.092V     934.2mV    1.29V
[Rising Waveform]
R_fixture = 50.000
V_fixture = 3.300
V_fixture_min = 3.200
V_fixture_max = 3.400
|  time   V(typ)   V(min)   V(max)
0s        2.206V     2.254V     2.113V
425ps     2.207V     2.255V     2.141V
463ps     2.206V     2.255V     2.295V
532ps     2.265V     2.255V     2.877V
602ps     2.622V     2.27V      3.178V
667ps     2.975V     2.42V      3.288V
747ps     3.158V     2.775V     3.346V
868ps     3.251V     3.069V     3.379V
1.097ns   3.291V     3.178V     3.395V
50ns      3.3V       3.2V       3.4V
[Falling Waveform]
R_fixture = 50.000
V_fixture = 3.300
V_fixture_min = 3.200
V_fixture_max = 3.400
|  time   V(typ)   V(min)   V(max)
0s        3.3V       3.2V       3.4V
483ps     3.301V     3.2V       3.337V
542ps     3.288V     3.2V       3.175V
609ps     3.22V      3.199V     2.774V
681ps     2.994V     3.171V     2.42V
773ps     2.584V     3.048V     2.237V
859ps     2.377V     2.78V      2.173V
999ps     2.262V     2.443V     2.135V
1.2ns     2.222V     2.302V     2.121V
50ns      2.206V     2.254V     2.113V
[Falling Waveform]
R_fixture = 50.000
V_fixture = 0.000
V_fixture_min = 0.000
V_fixture_max = 0.000
|  time   V(typ)   V(min)   V(max)
0s        1.092V     934.2mV    1.29V
458ps     1.093V     933.9mV    1.242V
508ps     1.089V     934mV      1.046V
578ps     1.016V     934.4mV    475.1mV
651ps     639.3mV    913mV      197.1mV
703ps     338.9mV    832mV      112.2mV
783ps     144mV      471.1mV    49.19mV
891ps     50.38mV    150.5mV    17.03mV
1.082ns   8.778mV    26.32mV    2.92mV
50ns      117uV      -10.83uV   49.78uV
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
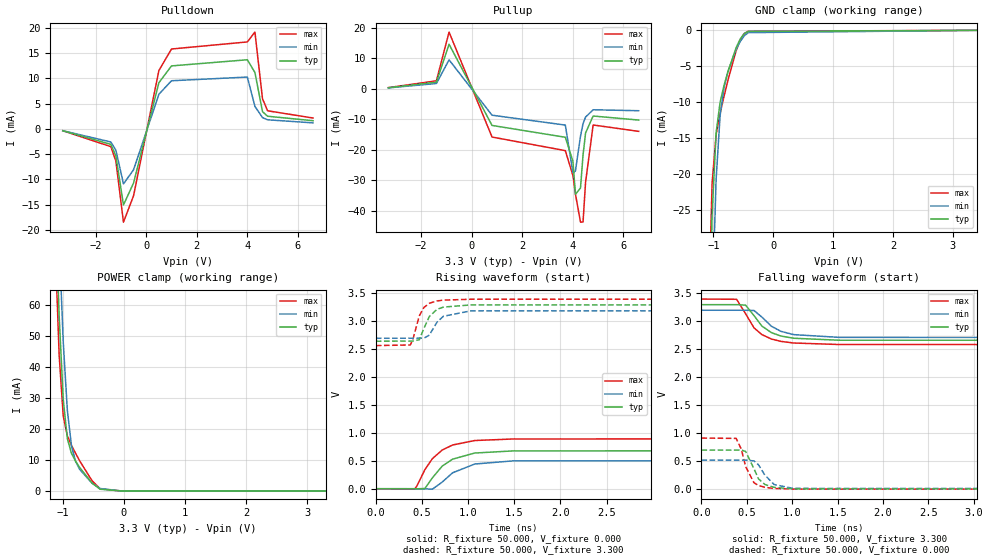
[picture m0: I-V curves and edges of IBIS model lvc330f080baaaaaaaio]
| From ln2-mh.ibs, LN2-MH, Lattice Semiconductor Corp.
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|   Model lvc330f080baaaaaaaio
[Model] lvc330f080baaaaaaaio
Model_type I/O
Polarity   Non-Inverting
Enable   Active-Low
Vinl =  0.800V
Vinh =  2.000V
Vmeas =  1.650V
Cref =  0.0F
Rref =  1.000M
Vref =  0.0V
C_comp   2.000pF   1.500pF   2.500pF
[Temperature Range]   25.000   0.125k   -40.000
[Voltage Range]   3.300V   3.200V   3.400V
[C Comp Corner]
C_comp   2.000pF   1.500pF   2.500pF
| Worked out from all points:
|   slope of the pulldown table from 0 to 0.495 V, typ, clamps not added: 55.2 ohm
|   slope of the pullup table from 0 to 0.495 V, typ, clamps not added: 55.2 ohm
|   GND clamp passes 1 mA (typ) near -0.53 V on its own axis
|   POWER clamp passes 1 mA (typ) near -0.42 V on its own axis
|   rising waveform, R_fixture 50.000, V_fixture 0.000: 20-80 % time 280ps typ, 294ps min, 275ps max; typ from 0 V to 0.699 V
|   rising waveform, R_fixture 50.000, V_fixture 3.300: 20-80 % time 122ps typ, 146ps min, 104ps max; typ from 2.64 V to 3.3 V
|   falling waveform, R_fixture 50.000, V_fixture 3.300: 20-80 % time 255ps typ, 271ps min, 245ps max; typ from 3.3 V to 2.64 V
|   falling waveform, R_fixture 50.000, V_fixture 0.000: 20-80 % time 119ps typ, 137ps min, 105ps max; typ from 0.699 V to 0 V
[Pulldown]
|Voltage   I(typ)   I(min)   I(max)
-3.3V     -350.9uA   -349.7uA   -349.9uA
-1.4V     -3.048mA   -2.58mA    -3.499mA
-1.2V     -5.336mA   -4.195mA   -6.363mA
-900mV    -15.06mA   -10.88mA   -18.47mA
-500mV    -10.7mA    -8.078mA   -13.22mA
500mV     9.141mA    6.873mA    11.56mA
1V        12.49mA    9.55mA     15.84mA
4V        13.71mA    10.28mA    17.24mA
4.3V      11.18mA    4.469mA    19.19mA
4.6V      3.432mA    2.253mA    5.984mA
4.8V      2.519mA    1.816mA    3.602mA
6.6V      1.633mA    1.204mA    2.166mA
[Pullup]
|Voltage   I(typ)   I(min)   I(max)
-3.3V     342.6uA    296.6uA    390.2uA
-1.4V     2.189mA    1.739mA    2.629mA
-900mV    14.63mA    9.513mA    18.62mA
800mV     -12.02mA   -8.67mA    -15.83mA
3.7V      -15.91mA   -11.91mA   -20.3mA
4V        -23.8mA    -27.58mA   -28.49mA
4.1V      -34.62mA   -26.96mA   -34.57mA
4.3V      -32.55mA   -15.49mA   -43.79mA
4.4V      -21.75mA   -11.43mA   -43.71mA
4.5V      -14.49mA   -9.283mA   -30.7mA
4.8V      -8.936mA   -6.878mA   -11.88mA
6.6V      -10.26mA   -7.197mA   -13.97mA
[GND_clamp]
|Voltage   I(typ)   I(min)   I(max)
-3.3V     -1.861A    -1.855A    -1.868A
-1.089V   -50.81mA   -68.21mA   -41.78mA
-1.022V   -25.75mA   -39.09mA   -21.32mA
-955mV    -14.27mA   -20.74mA   -14.55mA
-888mV    -9.999mA   -11.85mA   -11.57mA
-821mV    -7.623mA   -7.877mA   -9.132mA
-754mV    -5.679mA   -5.648mA   -6.844mA
-620mV    -2.407mA   -2.651mA   -2.831mA
-553mV    -1.221mA   -1.563mA   -1.361mA
-486mV    -463.6uA   -775.1uA   -445.5uA
-419mV    -157.8uA   -320.2uA   -132.1uA
3.4V      0A         0A         0A
[POWER_clamp]
|Voltage   I(typ)   I(min)   I(max)
-3.266V   2.002A     2.005A     2.003A
-1.122V   95.85mA    122.4mA    80.77mA
-1.055V   56.44mA    81.14mA    43.86mA
-988mV    29.49mA    48.07mA    24.19mA
-921mV    16.88mA    26.01mA    17.76mA
-854mV    12.16mA    14.63mA    14.72mA
-787mV    9.627mA    9.57mA     12.17mA
-720mV    7.572mA    6.968mA    9.725mA
-519mV    2.543mA    2.542mA    3.339mA
-385mV    550.4uA    786uA      665.7uA
-50mV     13.15uA    11.69uA    15.71uA
3.3V      0A         0A         0A
[Ramp]
| variable   typ   min   max
dV/dt_r   0.429/0.282n   0.319/0.294n   0.561/0.273n
dV/dt_f   0.403/0.255n   0.310/0.272n   0.511/0.244n
R_load = 50.000
[Rising Waveform]
R_fixture = 50.000
V_fixture = 0.000
V_fixture_min = 0.000
V_fixture_max = 0.000
|  time   V(typ)   V(min)   V(max)
0s        3.337uV    16.37uV    1.176uV
418ps     -90.39uV   -303.7uV   -5.497mV
443ps     -1.754mV   -294.5uV   43.2mV
531ps     3.861mV    -1.525mV   340.7mV
613ps     195.8mV    -7.984mV   539.6mV
718ps     403.8mV    117.8mV    692mV
832ps     530.3mV    286.2mV    784.2mV
1.072ns   639.8mV    443mV      864.1mV
1.492ns   678.3mV    499.9mV    891.9mV
50ns      699mV      519.6mV    914mV
[Rising Waveform]
R_fixture = 50.000
V_fixture = 3.300
V_fixture_min = 3.200
V_fixture_max = 3.400
|  time   V(typ)   V(min)   V(max)
0s        2.644V     2.697V     2.566V
373ps     2.647V     2.698V     2.577V
400ps     2.647V     2.698V     2.67V
471ps     2.671V     2.699V     3.1V
520ps     2.871V     2.699V     3.247V
580ps     3.089V     2.754V     3.325V
662ps     3.215V     2.984V     3.366V
732ps     3.256V     3.092V     3.381V
1.032ns   3.295V     3.189V     3.397V
50ns      3.3V       3.2V       3.4V
[Falling Waveform]
R_fixture = 50.000
V_fixture = 3.300
V_fixture_min = 3.200
V_fixture_max = 3.400
|  time   V(typ)   V(min)   V(max)
0s        3.3V       3.2V       3.4V
387ps     3.3V       3.2V       3.396V
486ps     3.291V     3.2V       3.138V
579ps     3.104V     3.195V     2.885V
665ps     2.918V     3.078V     2.765V
771ps     2.799V     2.914V     2.685V
875ps     2.739V     2.823V     2.643V
1.016ns   2.699V     2.764V     2.614V
1.516ns   2.664V     2.715V     2.587V
50ns      2.644V     2.697V     2.566V
[Falling Waveform]
R_fixture = 50.000
V_fixture = 0.000
V_fixture_min = 0.000
V_fixture_max = 0.000
|  time   V(typ)   V(min)   V(max)
0s        699mV      519.6mV    914mV
382ps     698.6mV    519.3mV    907.9mV
439ps     700.1mV    519.2mV    714.5mV
487ps     674.2mV    519.1mV    403.2mV
578ps     366.8mV    505.9mV    115.4mV
628ps     185mV      436.1mV    66.43mV
698ps     84.5mV     253.4mV    32.86mV
800ps     32.07mV    83.12mV    12.62mV
1.009ns   5.263mV    14.13mV    1.959mV
50ns      3.337uV    16.37uV    1.176uV
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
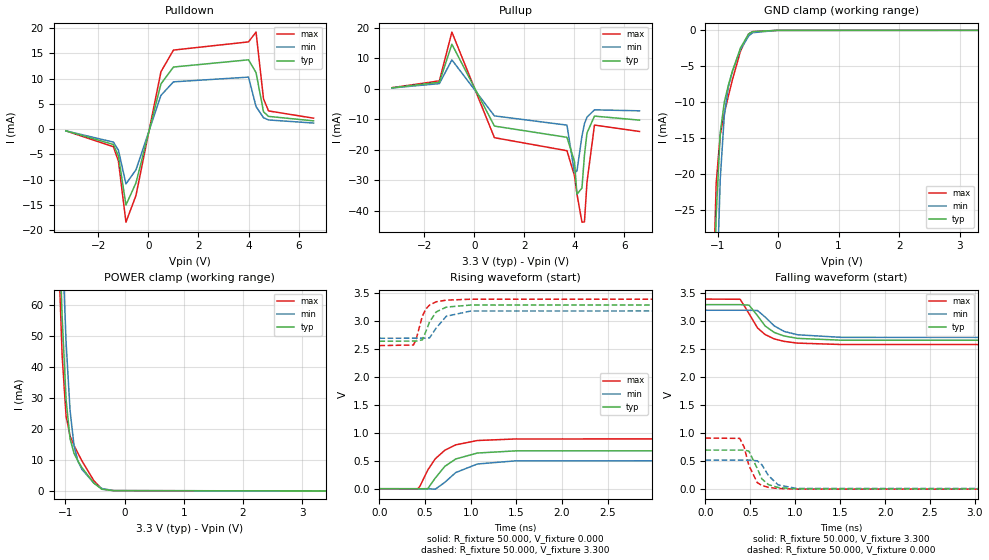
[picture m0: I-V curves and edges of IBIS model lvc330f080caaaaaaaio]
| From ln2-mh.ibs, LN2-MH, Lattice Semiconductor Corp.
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|   Model lvc330f080caaaaaaaio
[Model] lvc330f080caaaaaaaio
Model_type I/O
Polarity   Non-Inverting
Enable   Active-Low
Vinl =  0.800V
Vinh =  2.000V
Vmeas =  1.650V
Cref =  0.0F
Rref =  1.000M
Vref =  0.0V
C_comp   2.000pF   1.500pF   2.500pF
[Temperature Range]   25.000   0.125k   -40.000
[Voltage Range]   3.300V   3.200V   3.400V
[C Comp Corner]
C_comp   2.000pF   1.500pF   2.500pF
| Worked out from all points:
|   slope of the pulldown table from 0 to 0.495 V, typ, clamps not added: 55.7 ohm
|   slope of the pullup table from 0 to 0.495 V, typ, clamps not added: 54.7 ohm
|   GND clamp passes 1 mA (typ) near -0.53 V on its own axis
|   POWER clamp passes 1 mA (typ) near -0.42 V on its own axis
|   rising waveform, R_fixture 50.000, V_fixture 0.000: 20-80 % time 280ps typ, 293ps min, 275ps max; typ from 0 V to 0.699 V
|   rising waveform, R_fixture 50.000, V_fixture 3.300: 20-80 % time 122ps typ, 146ps min, 104ps max; typ from 2.64 V to 3.3 V
|   falling waveform, R_fixture 50.000, V_fixture 3.300: 20-80 % time 255ps typ, 271ps min, 245ps max; typ from 3.3 V to 2.64 V
|   falling waveform, R_fixture 50.000, V_fixture 0.000: 20-80 % time 118ps typ, 137ps min, 105ps max; typ from 0.699 V to 0 V
[Pulldown]
|Voltage   I(typ)   I(min)   I(max)
-3.3V     -346.1uA   -345.8uA   -343.9uA
-1.4V     -3.04mA    -2.574mA   -3.49mA
-1.2V     -5.324mA   -4.185mA   -6.348mA
-900mV    -15.03mA   -10.85mA   -18.43mA
-500mV    -10.66mA   -8.058mA   -13.16mA
500mV     8.96mA     6.694mA    11.38mA
1V        12.3mA     9.366mA    15.66mA
4V        13.73mA    10.3mA     17.28mA
4.3V      11.2mA     4.476mA    19.22mA
4.6V      3.437mA    2.256mA    5.992mA
4.8V      2.523mA    1.819mA    3.607mA
6.6V      1.635mA    1.206mA    2.169mA
[Pullup]
|Voltage   I(typ)   I(min)   I(max)
-3.3V     344.7uA    298uA      392.4uA
-1.4V     2.193mA    1.743mA    2.634mA
-900mV    14.66mA    9.528mA    18.65mA
800mV     -12.2mA    -8.854mA   -16.01mA
3.7V      -15.89mA   -11.89mA   -20.29mA
4V        -23.77mA   -27.55mA   -28.43mA
4.1V      -34.58mA   -26.93mA   -34.52mA
4.3V      -32.52mA   -15.48mA   -43.75mA
4.4V      -21.73mA   -11.42mA   -43.66mA
4.5V      -14.48mA   -9.275mA   -30.68mA
4.8V      -8.929mA   -6.872mA   -11.87mA
6.6V      -10.25mA   -7.193mA   -13.97mA
[GND_clamp]
|Voltage   I(typ)   I(min)   I(max)
-3.3V     -1.861A    -1.855A    -1.868A
-1.089V   -50.83mA   -68.22mA   -41.81mA
-1.022V   -25.77mA   -39.11mA   -21.36mA
-955mV    -14.31mA   -20.77mA   -14.6mA
-888mV    -10.03mA   -11.88mA   -11.61mA
-821mV    -7.659mA   -7.903mA   -9.179mA
-754mV    -5.715mA   -5.674mA   -6.892mA
-620mV    -2.446mA   -2.677mA   -2.886mA
-486mV    -500.9uA   -793.7uA   -505.5uA
-419mV    -184.7uA   -329.9uA   -181.9uA
-17mV     -4.77uA    -4.625uA   -5.541uA
3.3V      0A         0A         0A
[POWER_clamp]
|Voltage   I(typ)   I(min)   I(max)
-3.266V   2.002A     2.005A     2.003A
-1.122V   95.84mA    122.3mA    80.75mA
-1.055V   56.43mA    81.13mA    43.84mA
-988mV    29.47mA    48.06mA    24.16mA
-921mV    16.85mA    26mA       17.72mA
-854mV    12.14mA    14.62mA    14.69mA
-787mV    9.602mA    9.553mA    12.13mA
-720mV    7.548mA    6.952mA    9.693mA
-519mV    2.524mA    2.533mA    3.308mA
-385mV    541.5uA    790.3uA    641.3uA
-184mV    92.6uA     101.7uA    92.48uA
3.4V      0A         0A         0A
[Ramp]
| variable   typ   min   max
dV/dt_r   0.429/0.282n   0.319/0.294n   0.561/0.273n
dV/dt_f   0.403/0.255n   0.310/0.272n   0.511/0.244n
R_load = 50.000
[Rising Waveform]
R_fixture = 50.000
V_fixture = 0.000
V_fixture_min = 0.000
V_fixture_max = 0.000
|  time   V(typ)   V(min)   V(max)
0s        87.16uV    -5.445uV   35.24uV
418ps     11.13uV    -325.5uV   -5.329mV
443ps     -1.616mV   -316.3uV   43.58mV
529ps     1.271mV    -1.375mV   335mV
612ps     192.6mV    -8.16mV    537.9mV
716ps     400.5mV    114.2mV    689.9mV
836ps     533.4mV    290.6mV    786.6mV
1.072ns   639.7mV    443mV      864.1mV
1.492ns   678.3mV    499.9mV    891.9mV
50ns      699mV      519.6mV    914mV
[Rising Waveform]
R_fixture = 50.000
V_fixture = 3.300
V_fixture_min = 3.200
V_fixture_max = 3.400
|  time   V(typ)   V(min)   V(max)
0s        2.644V     2.697V     2.566V
372ps     2.647V     2.698V     2.576V
400ps     2.647V     2.698V     2.67V
470ps     2.669V     2.699V     3.095V
509ps     2.822V     2.7V       3.224V
549ps     2.991V     2.705V     3.293V
621ps     3.169V     2.88V      3.351V
732ps     3.256V     3.092V     3.381V
1.001ns   3.293V     3.186V     3.397V
50ns      3.3V       3.2V       3.4V
[Falling Waveform]
R_fixture = 50.000
V_fixture = 3.300
V_fixture_min = 3.200
V_fixture_max = 3.400
|  time   V(typ)   V(min)   V(max)
0s        3.3V       3.2V       3.4V
387ps     3.3V       3.2V       3.396V
486ps     3.291V     3.2V       3.138V
580ps     3.102V     3.195V     2.883V
665ps     2.918V     3.078V     2.765V
767ps     2.802V     2.919V     2.687V
877ps     2.739V     2.821V     2.643V
1.027ns   2.697V     2.761V     2.612V
1.516ns   2.664V     2.715V     2.587V
50ns      2.644V     2.697V     2.566V
[Falling Waveform]
R_fixture = 50.000
V_fixture = 0.000
V_fixture_min = 0.000
V_fixture_max = 0.000
|  time   V(typ)   V(min)   V(max)
0s        699mV      519.6mV    914mV
382ps     698.6mV    519.3mV    908.3mV
431ps     699.3mV    519.2mV    753.7mV
484ps     679.7mV    519.1mV    424mV
577ps     371.1mV    507mV      117mV
629ps     182.8mV    434.9mV    65.9mV
702ps     81.09mV    242.2mV    31.72mV
810ps     29.35mV    75.82mV    11.56mV
1.012ns   5.207mV    13.81mV    1.947mV
50ns      87.16uV    -5.445uV   35.24uV
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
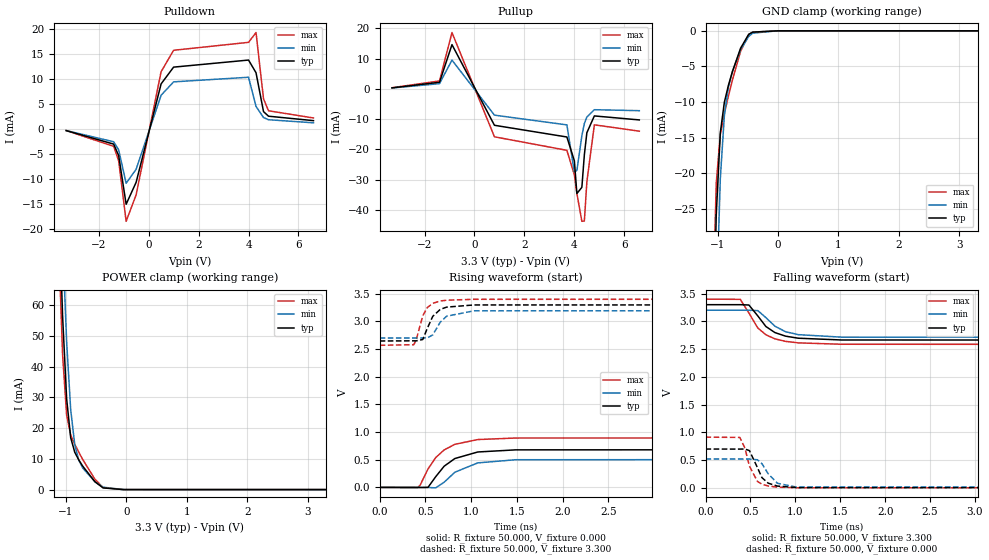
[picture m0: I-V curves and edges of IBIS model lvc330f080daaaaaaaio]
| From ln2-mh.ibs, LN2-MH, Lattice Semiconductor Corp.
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|   Model lvc330f080daaaaaaaio
[Model] lvc330f080daaaaaaaio
Model_type I/O
Polarity   Non-Inverting
Enable   Active-Low
Vinl =  0.800V
Vinh =  2.000V
Vmeas =  1.650V
Cref =  0.0F
Rref =  1.000M
Vref =  0.0V
C_comp   2.000pF   1.500pF   2.500pF
[Temperature Range]   25.000   0.125k   -40.000
[Voltage Range]   3.300V   3.200V   3.400V
[C Comp Corner]
C_comp   2.000pF   1.500pF   2.500pF
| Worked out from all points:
|   slope of the pulldown table from 0 to 0.495 V, typ, clamps not added: 55.7 ohm
|   slope of the pullup table from 0 to 0.495 V, typ, clamps not added: 55.2 ohm
|   GND clamp passes 1 mA (typ) near -0.53 V on its own axis
|   POWER clamp passes 1 mA (typ) near -0.42 V on its own axis
|   rising waveform, R_fixture 50.000, V_fixture 0.000: 20-80 % time 280ps typ, 293ps min, 275ps max; typ from 0 V to 0.699 V
|   rising waveform, R_fixture 50.000, V_fixture 3.300: 20-80 % time 122ps typ, 146ps min, 104ps max; typ from 2.64 V to 3.3 V
|   falling waveform, R_fixture 50.000, V_fixture 3.300: 20-80 % time 255ps typ, 271ps min, 245ps max; typ from 3.3 V to 2.64 V
|   falling waveform, R_fixture 50.000, V_fixture 0.000: 20-80 % time 119ps typ, 137ps min, 105ps max; typ from 0.699 V to 0 V
[Pulldown]
|Voltage   I(typ)   I(min)   I(max)
-3.3V     -346.1uA   -345.8uA   -343.9uA
-1.4V     -3.04mA    -2.574mA   -3.49mA
-1.2V     -5.324mA   -4.185mA   -6.348mA
-900mV    -15.03mA   -10.85mA   -18.43mA
-500mV    -10.66mA   -8.058mA   -13.16mA
500mV     8.96mA     6.694mA    11.38mA
1V        12.3mA     9.366mA    15.66mA
4V        13.71mA    10.28mA    17.24mA
4.3V      11.18mA    4.469mA    19.19mA
4.6V      3.432mA    2.253mA    5.984mA
4.8V      2.519mA    1.816mA    3.602mA
6.6V      1.633mA    1.204mA    2.166mA
[Pullup]
|Voltage   I(typ)   I(min)   I(max)
-3.3V     342.6uA    296.6uA    390.2uA
-1.4V     2.189mA    1.739mA    2.629mA
-900mV    14.63mA    9.513mA    18.62mA
800mV     -12.02mA   -8.67mA    -15.83mA
3.7V      -15.89mA   -11.89mA   -20.29mA
4V        -23.77mA   -27.55mA   -28.43mA
4.1V      -34.58mA   -26.93mA   -34.52mA
4.3V      -32.52mA   -15.48mA   -43.75mA
4.4V      -21.73mA   -11.42mA   -43.66mA
4.5V      -14.48mA   -9.275mA   -30.68mA
4.8V      -8.929mA   -6.872mA   -11.87mA
6.6V      -10.25mA   -7.193mA   -13.97mA
[GND_clamp]
|Voltage   I(typ)   I(min)   I(max)
-3.3V     -1.861A    -1.855A    -1.868A
-1.089V   -50.83mA   -68.22mA   -41.81mA
-1.022V   -25.77mA   -39.11mA   -21.36mA
-955mV    -14.31mA   -20.77mA   -14.6mA
-888mV    -10.03mA   -11.88mA   -11.61mA
-821mV    -7.659mA   -7.903mA   -9.179mA
-754mV    -5.715mA   -5.674mA   -6.892mA
-620mV    -2.446mA   -2.677mA   -2.886mA
-486mV    -500.9uA   -793.7uA   -505.5uA
-419mV    -184.7uA   -329.9uA   -181.9uA
-17mV     -4.77uA    -4.625uA   -5.541uA
3.3V      -213nA     0A         -30.51uA
[POWER_clamp]
|Voltage   I(typ)   I(min)   I(max)
-3.266V   2.002A     2.005A     2.003A
-1.122V   95.85mA    122.4mA    80.77mA
-1.055V   56.44mA    81.14mA    43.86mA
-988mV    29.49mA    48.07mA    24.19mA
-921mV    16.88mA    26.01mA    17.76mA
-854mV    12.16mA    14.63mA    14.72mA
-787mV    9.627mA    9.57mA     12.17mA
-720mV    7.572mA    6.968mA    9.725mA
-519mV    2.543mA    2.542mA    3.339mA
-385mV    550.4uA    786uA      665.7uA
-50mV     13.15uA    11.69uA    15.71uA
3.3V      0A         0A         30.92uA
[Ramp]
| variable   typ   min   max
dV/dt_r   0.429/0.282n   0.319/0.295n   0.561/0.273n
dV/dt_f   0.403/0.255n   0.310/0.272n   0.511/0.244n
R_load = 50.000
[Rising Waveform]
R_fixture = 50.000
V_fixture = 0.000
V_fixture_min = 0.000
V_fixture_max = 0.000
|  time   V(typ)   V(min)   V(max)
0s        87.16uV    -5.445uV   35.24uV
418ps     12.49uV    -325.5uV   -5.281mV
443ps     -1.637mV   -316.3uV   43.76mV
528ps     395.3uV    -1.289mV   332.2mV
612ps     192.9mV    -8.161mV   538.1mV
705ps     383.6mV    94.52mV    677.7mV
822ps     521.9mV    274.7mV    778.3mV
1.072ns   639.8mV    443mV      864.1mV
1.486ns   678.1mV    499.7mV    891.8mV
50ns      699mV      519.6mV    914mV
[Rising Waveform]
R_fixture = 50.000
V_fixture = 3.300
V_fixture_min = 3.200
V_fixture_max = 3.400
|  time   V(typ)   V(min)   V(max)
0s        2.644V     2.697V     2.566V
373ps     2.647V     2.698V     2.577V
400ps     2.647V     2.698V     2.67V
471ps     2.671V     2.699V     3.1V
519ps     2.867V     2.699V     3.245V
580ps     3.089V     2.754V     3.325V
662ps     3.215V     2.984V     3.366V
732ps     3.256V     3.092V     3.381V
1.032ns   3.295V     3.189V     3.397V
50ns      3.3V       3.2V       3.4V
[Falling Waveform]
R_fixture = 50.000
V_fixture = 3.300
V_fixture_min = 3.200
V_fixture_max = 3.400
|  time   V(typ)   V(min)   V(max)
0s        3.3V       3.2V       3.4V
387ps     3.3V       3.2V       3.396V
483ps     3.294V     3.2V       3.15V
582ps     3.098V     3.193V     2.88V
672ps     2.907V     3.067V     2.758V
772ps     2.798V     2.913V     2.685V
891ps     2.733V     2.813V     2.639V
1.032ns   2.696V     2.76V      2.612V
1.514ns   2.664V     2.715V     2.587V
50ns      2.644V     2.697V     2.566V
[Falling Waveform]
R_fixture = 50.000
V_fixture = 0.000
V_fixture_min = 0.000
V_fixture_max = 0.000
|  time   V(typ)   V(min)   V(max)
0s        699mV      519.6mV    914mV
382ps     698.6mV    519.3mV    908.4mV
439ps     700.1mV    519.2mV    715.5mV
489ps     670.5mV    519.1mV    391.8mV
578ps     365.4mV    506.1mV    115.6mV
628ps     184.4mV    436.5mV    66.51mV
698ps     84.32mV    254mV      32.92mV
800ps     32.06mV    83.26mV    12.66mV
1.01ns    5.29mV     14.02mV    1.979mV
50ns      87.16uV    -5.445uV   35.24uV
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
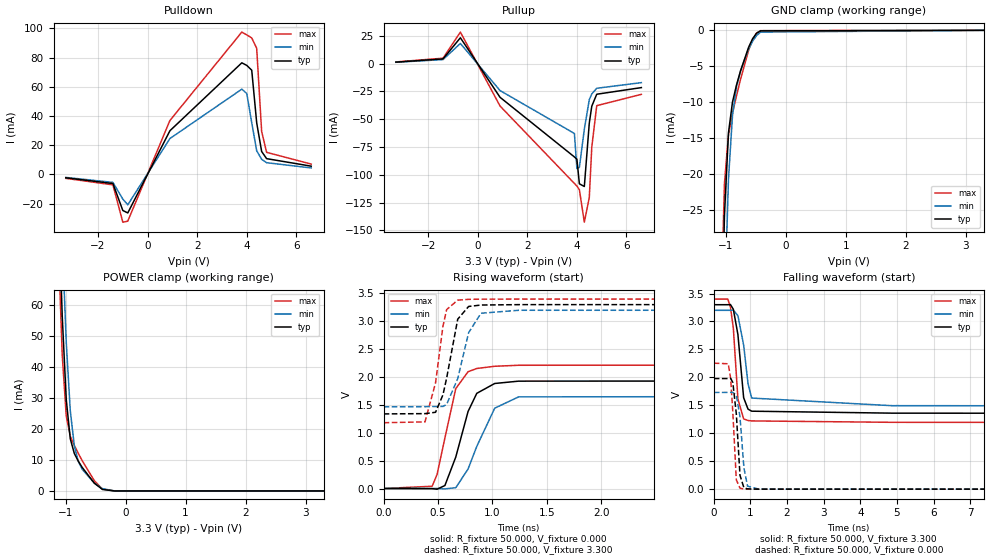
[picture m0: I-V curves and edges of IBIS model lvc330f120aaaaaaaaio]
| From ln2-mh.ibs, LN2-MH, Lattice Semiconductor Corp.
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|   Model lvc330f120aaaaaaaaio
[Model] lvc330f120aaaaaaaaio
Model_type I/O
Polarity   Non-Inverting
Enable   Active-Low
Vinl =  0.800V
Vinh =  2.000V
Vmeas =  1.650V
Cref =  0.0F
Rref =  1.000M
Vref =  0.0V
C_comp   2.000pF   1.500pF   2.500pF
[Temperature Range]   25.000   0.125k   -40.000
[Voltage Range]   3.300V   3.200V   3.400V
[C Comp Corner]
C_comp   2.000pF   1.500pF   2.500pF
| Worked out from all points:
|   slope of the pulldown table from 0 to 0.495 V, typ, clamps not added: 26.6 ohm
|   slope of the pullup table from 0 to 0.495 V, typ, clamps not added: 26.5 ohm
|   GND clamp passes 1 mA (typ) near -0.54 V on its own axis
|   POWER clamp passes 1 mA (typ) near -0.43 V on its own axis
|   rising waveform, R_fixture 50.000, V_fixture 0.000: 20-80 % time 178ps typ, 223ps min, 149ps max; typ from 0 V to 1.98 V
|   rising waveform, R_fixture 50.000, V_fixture 3.300: 20-80 % time 111ps typ, 132ps min, 94.9ps max; typ from 1.34 V to 3.3 V
|   falling waveform, R_fixture 50.000, V_fixture 3.300: 20-80 % time 156ps typ, 194ps min, 133ps max; typ from 3.3 V to 1.34 V
|   falling waveform, R_fixture 50.000, V_fixture 0.000: 20-80 % time 110ps typ, 126ps min, 99.5ps max; typ from 1.98 V to 0 V
[Pulldown]
|Voltage   I(typ)   I(min)   I(max)
-3.3V     -2.345mA   -2.076mA   -2.727mA
-1.4V     -6.266mA   -5.489mA   -7.185mA
-1V       -24.72mA   -16.92mA   -32.74mA
-800mV    -26.41mA   -20.84mA   -32.04mA
900mV     29.87mA    24.53mA    36.9mA
3.8V      76.38mA    58.35mA    97.42mA
4V        74.61mA    55.38mA    95.49mA
4.2V      71.32mA    35.39mA    93.42mA
4.4V      35.34mA    16.18mA    86.33mA
4.6V      15.67mA    10.33mA    29.42mA
4.8V      10.77mA    7.994mA    15.09mA
6.6V      5.609mA    4.392mA    7.052mA
[Pullup]
|Voltage   I(typ)   I(min)   I(max)
-3.3V     1.285mA    1.145mA    1.475mA
-1.4V     4.192mA    3.596mA    4.847mA
-700mV    23.22mA    18.08mA    28.31mA
900mV     -30.32mA   -24.27mA   -38.17mA
3.9V      -83.95mA   -62.85mA   -107.8mA
4V        -85.99mA   -94.43mA   -110.1mA
4.1V      -108.1mA   -93.26mA   -113.4mA
4.3V      -110.5mA   -58.99mA   -142.6mA
4.5V      -53.47mA   -32.45mA   -120.4mA
4.6V      -38.36mA   -27.32mA   -75.28mA
4.8V      -27.56mA   -22.19mA   -37.84mA
6.6V      -21.6mA    -17.14mA   -27.66mA
[GND_clamp]
|Voltage   I(typ)   I(min)   I(max)
-3.3V     -1.861A    -1.855A    -1.868A
-1.089V   -50.81mA   -68.2mA    -41.77mA
-1.022V   -25.74mA   -39.08mA   -21.31mA
-955mV    -14.26mA   -20.73mA   -14.54mA
-888mV    -9.982mA   -11.84mA   -11.55mA
-821mV    -7.603mA   -7.856mA   -9.113mA
-754mV    -5.655mA   -5.623mA   -6.821mA
-620mV    -2.371mA   -2.616mA   -2.797mA
-553mV    -1.172mA   -1.518mA   -1.313mA
-486mV    -396.2uA   -716.4uA   -376.4uA
-419mV    -71.95uA   -244.9uA   -42.84uA
3.3V      0A         0A         0A
[POWER_clamp]
|Voltage   I(typ)   I(min)   I(max)
-3.266V   2.002A     2.005A     2.003A
-1.122V   95.84mA    122.3mA    80.75mA
-1.055V   56.42mA    81.13mA    43.84mA
-988mV    29.46mA    48.05mA    24.15mA
-921mV    16.84mA    25.99mA    17.71mA
-854mV    12.12mA    14.6mA     14.67mA
-787mV    9.585mA    9.535mA    12.12mA
-720mV    7.529mA    6.931mA    9.676mA
-519mV    2.487mA    2.496mA    3.276mA
-385mV    477.3uA    731.6uA    579.8uA
-184mV    1.009uA    11.15uA    276.7nA
3.3V      0A         0A         0A
[Ramp]
| variable   typ   min   max
dV/dt_r   1.214/0.178n   1.062/0.223n   1.381/0.149n
dV/dt_f   1.203/0.156n   1.064/0.195n   1.360/0.134n
R_load = 50.000
[Rising Waveform]
R_fixture = 50.000
V_fixture = 0.000
V_fixture_min = 0.000
V_fixture_max = 0.000
|  time   V(typ)   V(min)   V(max)
0s        1.645uV    6.732uV    585.8nV
446ps     -2.115mV   -279.7uV   41.01mV
491ps     -11.63mV   -18.26uV   252.3mV
563ps     53.38mV    -6.663mV   905.5mV
663ps     564.7mV    14.75mV    1.793V
776ps     1.382V     349.3mV    2.096V
856ps     1.708V     755.3mV    2.154V
1.021ns   1.885V     1.442V     2.194V
1.241ns   1.927V     1.645V     2.212V
50ns      1.979V     1.73V      2.254V
[Rising Waveform]
R_fixture = 50.000
V_fixture = 3.300
V_fixture_min = 3.200
V_fixture_max = 3.400
|  time   V(typ)   V(min)   V(max)
0s        1.339V     1.466V     1.181V
380ps     1.344V     1.469V     1.196V
477ps     1.368V     1.472V     1.895V
545ps     1.68V      1.473V     2.91V
579ps     1.981V     1.509V     3.211V
681ps     3.039V     1.973V     3.381V
781ps     3.267V     2.796V     3.395V
895ps     3.293V     3.146V     3.398V
1.245ns   3.3V       3.199V     3.4V
50ns      3.3V       3.2V       3.4V
[Falling Waveform]
R_fixture = 50.000
V_fixture = 3.300
V_fixture_min = 3.200
V_fixture_max = 3.400
|  time   V(typ)   V(min)   V(max)
0s        3.3V       3.2V       3.4V
383ps     3.3V       3.2V       3.401V
455ps     3.303V     3.2V       3.256V
534ps     3.219V     3.202V     2.88V
659ps     2.764V     3.104V     1.612V
815ps     1.636V     2.578V     1.257V
935ps     1.432V     1.887V     1.228V
1.035ns   1.395V     1.63V      1.221V
4.847ns   1.36V      1.494V     1.196V
50ns      1.339V     1.466V     1.181V
[Falling Waveform]
R_fixture = 50.000
V_fixture = 0.000
V_fixture_min = 0.000
V_fixture_max = 0.000
|  time   V(typ)   V(min)   V(max)
0s        1.979V     1.73V      2.254V
395ps     1.979V     1.731V     2.243V
461ps     1.982V     1.731V     1.981V
520ps     1.908V     1.731V     1.375V
615ps     1.348V     1.685V     168mV
715ps     249.8mV    1.299V     17.88mV
822ps     25.75mV    385mV      3.088mV
921ps     5.1mV      53.51mV    871.6uV
1.224ns   222.7uV    859.3uV    126.3uV
50ns      1.645uV    6.732uV    579.9nV
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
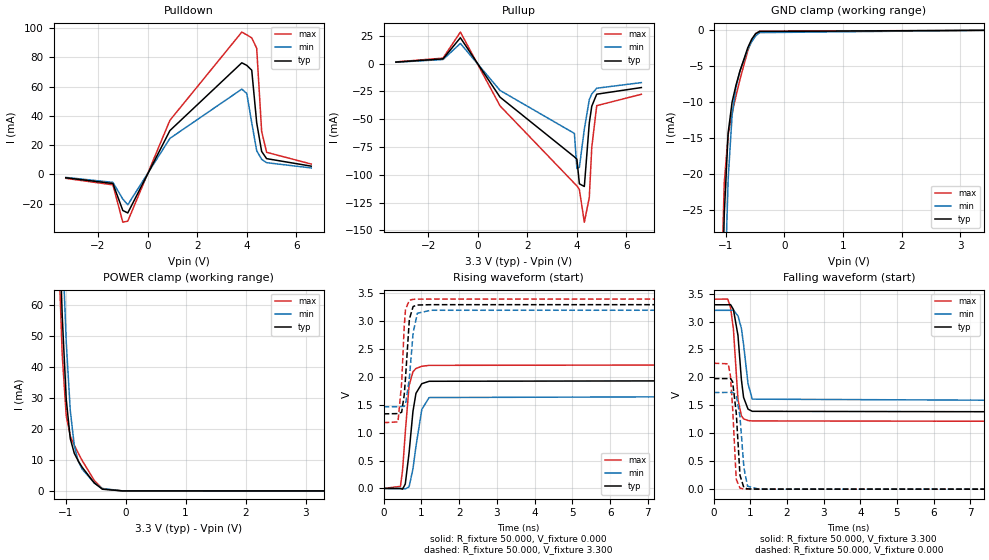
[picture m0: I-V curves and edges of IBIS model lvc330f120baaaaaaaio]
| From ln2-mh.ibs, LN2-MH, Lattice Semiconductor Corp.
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|   Model lvc330f120baaaaaaaio
[Model] lvc330f120baaaaaaaio
Model_type I/O
Polarity   Non-Inverting
Enable   Active-Low
Vinl =  0.800V
Vinh =  2.000V
Vmeas =  1.650V
Cref =  0.0F
Rref =  1.000M
Vref =  0.0V
C_comp   2.000pF   1.500pF   2.500pF
[Temperature Range]   25.000   0.125k   -40.000
[Voltage Range]   3.300V   3.200V   3.400V
[C Comp Corner]
C_comp   2.000pF   1.500pF   2.500pF
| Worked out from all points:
|   slope of the pulldown table from 0 to 0.495 V, typ, clamps not added: 26.6 ohm
|   slope of the pullup table from 0 to 0.495 V, typ, clamps not added: 26.6 ohm
|   GND clamp passes 1 mA (typ) near -0.53 V on its own axis
|   POWER clamp passes 1 mA (typ) near -0.42 V on its own axis
|   rising waveform, R_fixture 50.000, V_fixture 0.000: 20-80 % time 178ps typ, 223ps min, 149ps max; typ from 0 V to 1.98 V
|   rising waveform, R_fixture 50.000, V_fixture 3.300: 20-80 % time 111ps typ, 132ps min, 94.9ps max; typ from 1.34 V to 3.3 V
|   falling waveform, R_fixture 50.000, V_fixture 3.300: 20-80 % time 156ps typ, 194ps min, 134ps max; typ from 3.3 V to 1.34 V
|   falling waveform, R_fixture 50.000, V_fixture 0.000: 20-80 % time 110ps typ, 126ps min, 99.5ps max; typ from 1.98 V to 0 V
[Pulldown]
|Voltage   I(typ)   I(min)   I(max)
-3.3V     -2.343mA   -2.074mA   -2.726mA
-1.4V     -6.263mA   -5.486mA   -7.183mA
-1V       -24.71mA   -16.91mA   -32.72mA
-800mV    -26.39mA   -20.82mA   -32.02mA
900mV     29.96mA    24.63mA    36.99mA
3.8V      76.32mA    58.31mA    97.33mA
4V        74.56mA    55.35mA    95.44mA
4.2V      71.28mA    35.37mA    93.37mA
4.4V      35.32mA    16.17mA    86.3mA
4.6V      15.66mA    10.32mA    29.41mA
4.8V      10.76mA    7.99mA     15.09mA
6.6V      5.607mA    4.39mA     7.049mA
[Pullup]
|Voltage   I(typ)   I(min)   I(max)
-3.3V     1.282mA    1.143mA    1.472mA
-1.4V     4.186mA    3.591mA    4.84mA
-700mV    23.18mA    18.05mA    28.26mA
900mV     -30.23mA   -24.18mA   -38.08mA
3.9V      -83.91mA   -62.82mA   -107.7mA
4V        -85.97mA   -94.41mA   -110mA
4.1V      -108.1mA   -93.25mA   -113.3mA
4.3V      -110.5mA   -58.98mA   -142.6mA
4.5V      -53.47mA   -32.44mA   -120.4mA
4.6V      -38.35mA   -27.32mA   -75.28mA
4.8V      -27.55mA   -22.19mA   -37.84mA
6.6V      -21.6mA    -17.14mA   -27.66mA
[GND_clamp]
|Voltage   I(typ)   I(min)   I(max)
-3.3V     -1.861A    -1.855A    -1.868A
-1.089V   -50.81mA   -68.21mA   -41.78mA
-1.022V   -25.75mA   -39.09mA   -21.32mA
-955mV    -14.27mA   -20.74mA   -14.55mA
-888mV    -9.999mA   -11.85mA   -11.57mA
-821mV    -7.623mA   -7.877mA   -9.132mA
-754mV    -5.679mA   -5.648mA   -6.844mA
-620mV    -2.407mA   -2.651mA   -2.831mA
-553mV    -1.221mA   -1.563mA   -1.361mA
-486mV    -463.6uA   -775.1uA   -445.5uA
-419mV    -157.8uA   -320.2uA   -132.1uA
3.4V      0A         0A         0A
[POWER_clamp]
|Voltage   I(typ)   I(min)   I(max)
-3.266V   2.002A     2.005A     2.003A
-1.122V   95.85mA    122.4mA    80.77mA
-1.055V   56.44mA    81.14mA    43.86mA
-988mV    29.49mA    48.07mA    24.19mA
-921mV    16.88mA    26.01mA    17.76mA
-854mV    12.16mA    14.63mA    14.72mA
-787mV    9.627mA    9.57mA     12.17mA
-720mV    7.572mA    6.968mA    9.725mA
-519mV    2.543mA    2.542mA    3.339mA
-385mV    550.4uA    786uA      665.7uA
-50mV     13.15uA    11.69uA    15.71uA
3.3V      0A         0A         0A
[Ramp]
| variable   typ   min   max
dV/dt_r   1.214/0.178n   1.062/0.223n   1.381/0.149n
dV/dt_f   1.203/0.157n   1.064/0.195n   1.360/0.134n
R_load = 50.000
[Rising Waveform]
R_fixture = 50.000
V_fixture = 0.000
V_fixture_min = 0.000
V_fixture_max = 0.000
|  time   V(typ)   V(min)   V(max)
0s        1.645uV    6.731uV    586.4nV
445ps     -1.928mV   -281.6uV   37.78mV
500ps     -12.76mV   93.37uV    318.3mV
573ps     79.93mV    -8.389mV   1.005V
673ps     636.6mV    28.26mV    1.843V
776ps     1.382V     349.3mV    2.096V
856ps     1.708V     755.3mV    2.154V
1.011ns   1.881V     1.419V     2.193V
1.205ns   1.924V     1.632V     2.21V
50ns      1.979V     1.73V      2.254V
[Rising Waveform]
R_fixture = 50.000
V_fixture = 3.300
V_fixture_min = 3.200
V_fixture_max = 3.400
|  time   V(typ)   V(min)   V(max)
0s        1.339V     1.466V     1.181V
380ps     1.344V     1.469V     1.195V
477ps     1.368V     1.472V     1.892V
545ps     1.68V      1.473V     2.907V
579ps     1.981V     1.51V      3.21V
681ps     3.039V     1.974V     3.381V
781ps     3.267V     2.797V     3.395V
894ps     3.293V     3.145V     3.398V
1.246ns   3.299V     3.199V     3.4V
50ns      3.3V       3.2V       3.4V
[Falling Waveform]
R_fixture = 50.000
V_fixture = 3.300
V_fixture_min = 3.200
V_fixture_max = 3.400
|  time   V(typ)   V(min)   V(max)
0s        3.3V       3.2V       3.4V
381ps     3.3V       3.2V       3.402V
458ps     3.303V     3.2V       3.248V
536ps     3.215V     3.202V     2.863V
661ps     2.749V     3.101V     1.6V
754ps     1.959V     2.877V     1.314V
813ps     1.643V     2.59V      1.258V
934ps     1.433V     1.891V     1.228V
1.05ns    1.393V     1.611V     1.221V
50ns      1.339V     1.466V     1.181V
[Falling Waveform]
R_fixture = 50.000
V_fixture = 0.000
V_fixture_min = 0.000
V_fixture_max = 0.000
|  time   V(typ)   V(min)   V(max)
0s        1.979V     1.73V      2.254V
395ps     1.979V     1.731V     2.243V
455ps     1.982V     1.731V     2.023V
514ps     1.923V     1.731V     1.455V
613ps     1.367V     1.688V     177.9mV
715ps     249.8mV    1.299V     17.9mV
822ps     25.75mV    385mV      3.089mV
921ps     5.1mV      53.51mV    872.2uV
1.224ns   222.7uV    859.3uV    126.2uV
50ns      1.645uV    6.731uV    580.4nV
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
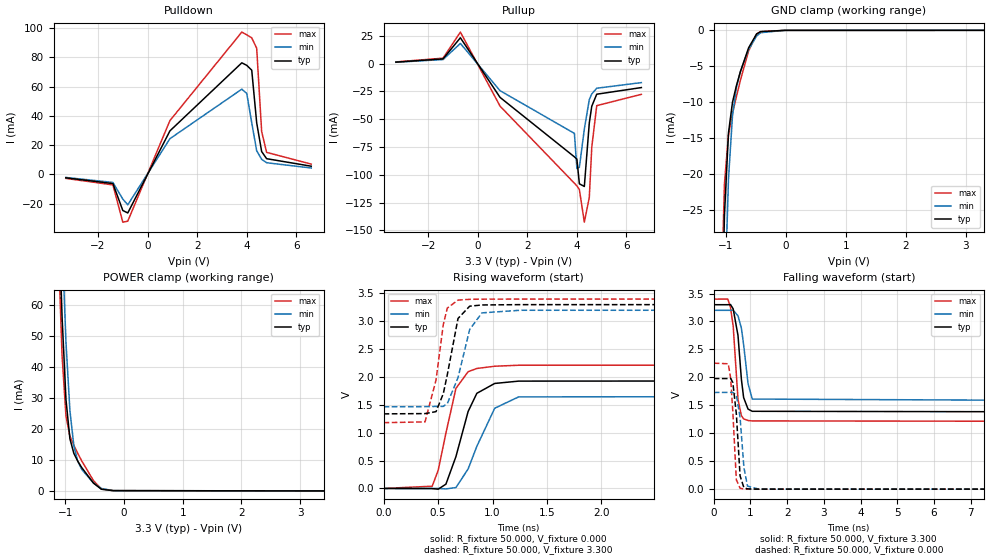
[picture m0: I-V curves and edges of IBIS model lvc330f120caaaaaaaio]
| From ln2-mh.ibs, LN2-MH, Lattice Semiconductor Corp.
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|   Model lvc330f120caaaaaaaio
[Model] lvc330f120caaaaaaaio
Model_type I/O
Polarity   Non-Inverting
Enable   Active-Low
Vinl =  0.800V
Vinh =  2.000V
Vmeas =  1.650V
Cref =  0.0F
Rref =  1.000M
Vref =  0.0V
C_comp   2.000pF   1.500pF   2.500pF
[Temperature Range]   25.000   0.125k   -40.000
[Voltage Range]   3.300V   3.200V   3.400V
[C Comp Corner]
C_comp   2.000pF   1.500pF   2.500pF
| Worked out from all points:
|   slope of the pulldown table from 0 to 0.495 V, typ, clamps not added: 26.7 ohm
|   slope of the pullup table from 0 to 0.495 V, typ, clamps not added: 26.5 ohm
|   GND clamp passes 1 mA (typ) near -0.53 V on its own axis
|   POWER clamp passes 1 mA (typ) near -0.42 V on its own axis
|   rising waveform, R_fixture 50.000, V_fixture 0.000: 20-80 % time 178ps typ, 223ps min, 149ps max; typ from 0 V to 1.98 V
|   rising waveform, R_fixture 50.000, V_fixture 3.300: 20-80 % time 111ps typ, 132ps min, 94.9ps max; typ from 1.34 V to 3.3 V
|   falling waveform, R_fixture 50.000, V_fixture 3.300: 20-80 % time 156ps typ, 194ps min, 134ps max; typ from 3.3 V to 1.34 V
|   falling waveform, R_fixture 50.000, V_fixture 0.000: 20-80 % time 110ps typ, 126ps min, 99.5ps max; typ from 1.98 V to 0 V
[Pulldown]
|Voltage   I(typ)   I(min)   I(max)
-3.3V     -2.338mA   -2.07mA    -2.72mA
-1.4V     -6.255mA   -5.479mA   -7.174mA
-1V       -24.68mA   -16.89mA   -32.68mA
-800mV    -26.36mA   -20.79mA   -31.98mA
900mV     29.78mA    24.44mA    36.81mA
3.8V      76.34mA    58.32mA    97.36mA
4V        74.59mA    55.36mA    95.47mA
4.2V      71.31mA    35.38mA    93.41mA
4.4V      35.33mA    16.18mA    86.32mA
4.6V      15.67mA    10.33mA    29.41mA
4.8V      10.76mA    7.992mA    15.09mA
6.6V      5.609mA    4.391mA    7.052mA
[Pullup]
|Voltage   I(typ)   I(min)   I(max)
-3.3V     1.285mA    1.144mA    1.475mA
-1.4V     4.19mA     3.594mA    4.845mA
-700mV    23.2mA     18.06mA    28.29mA
900mV     -30.42mA   -24.37mA   -38.26mA
3.9V      -83.87mA   -62.79mA   -107.6mA
4V        -85.93mA   -94.38mA   -110mA
4.1V      -108.1mA   -93.22mA   -113.3mA
4.3V      -110.5mA   -58.97mA   -142.6mA
4.5V      -53.45mA   -32.44mA   -120.4mA
4.6V      -38.35mA   -27.31mA   -75.26mA
4.8V      -27.55mA   -22.18mA   -37.83mA
6.6V      -21.59mA   -17.13mA   -27.66mA
[GND_clamp]
|Voltage   I(typ)   I(min)   I(max)
-3.3V     -1.861A    -1.855A    -1.868A
-1.089V   -50.83mA   -68.22mA   -41.81mA
-1.022V   -25.77mA   -39.11mA   -21.36mA
-955mV    -14.31mA   -20.77mA   -14.6mA
-888mV    -10.03mA   -11.88mA   -11.61mA
-821mV    -7.659mA   -7.903mA   -9.179mA
-754mV    -5.715mA   -5.674mA   -6.892mA
-620mV    -2.446mA   -2.677mA   -2.886mA
-486mV    -500.9uA   -793.7uA   -505.5uA
-419mV    -184.7uA   -329.9uA   -181.9uA
-17mV     -4.77uA    -4.625uA   -5.541uA
3.3V      0A         0A         0A
[POWER_clamp]
|Voltage   I(typ)   I(min)   I(max)
-3.266V   2.002A     2.005A     2.003A
-1.122V   95.84mA    122.3mA    80.75mA
-1.055V   56.43mA    81.13mA    43.84mA
-988mV    29.47mA    48.06mA    24.16mA
-921mV    16.85mA    26mA       17.72mA
-854mV    12.14mA    14.62mA    14.69mA
-787mV    9.602mA    9.553mA    12.13mA
-720mV    7.548mA    6.952mA    9.693mA
-519mV    2.524mA    2.533mA    3.308mA
-385mV    541.5uA    790.3uA    641.3uA
-184mV    92.6uA     101.7uA    92.48uA
3.4V      0A         0A         0A
[Ramp]
| variable   typ   min   max
dV/dt_r   1.214/0.178n   1.062/0.223n   1.381/0.149n
dV/dt_f   1.203/0.157n   1.064/0.195n   1.360/0.134n
R_load = 50.000
[Rising Waveform]
R_fixture = 50.000
V_fixture = 0.000
V_fixture_min = 0.000
V_fixture_max = 0.000
|  time   V(typ)   V(min)   V(max)
0s        58.57uV    -8.068uV   23.24uV
446ps     -2.058mV   -294.2uV   40.25mV
501ps     -12.78mV   92uV       325.2mV
572ps     77.12mV    -8.243mV   994.1mV
664ps     571.9mV    16.17mV    1.797V
776ps     1.382V     350mV      2.096V
856ps     1.708V     755.9mV    2.154V
1.02ns    1.885V     1.44V      2.194V
1.24ns    1.927V     1.644V     2.212V
50ns      1.979V     1.73V      2.254V
[Rising Waveform]
R_fixture = 50.000
V_fixture = 3.300
V_fixture_min = 3.200
V_fixture_max = 3.400
|  time   V(typ)   V(min)   V(max)
0s        1.339V     1.466V     1.181V
380ps     1.344V     1.469V     1.195V
481ps     1.379V     1.472V     1.946V
548ps     1.702V     1.474V     2.945V
585ps     2.045V     1.524V     3.239V
683ps     3.051V     1.988V     3.382V
790ps     3.272V     2.853V     3.395V
903ps     3.294V     3.152V     3.398V
1.254ns   3.3V       3.199V     3.4V
50ns      3.3V       3.2V       3.4V
[Falling Waveform]
R_fixture = 50.000
V_fixture = 3.300
V_fixture_min = 3.200
V_fixture_max = 3.400
|  time   V(typ)   V(min)   V(max)
0s        3.3V       3.2V       3.4V
383ps     3.3V       3.2V       3.401V
456ps     3.303V     3.2V       3.253V
529ps     3.226V     3.201V     2.919V
661ps     2.746V     3.101V     1.601V
753ps     1.964V     2.88V      1.315V
814ps     1.638V     2.583V     1.258V
934ps     1.433V     1.891V     1.228V
1.049ns   1.393V     1.612V     1.221V
50ns      1.339V     1.466V     1.181V
[Falling Waveform]
R_fixture = 50.000
V_fixture = 0.000
V_fixture_min = 0.000
V_fixture_max = 0.000
|  time   V(typ)   V(min)   V(max)
0s        1.979V     1.73V      2.254V
395ps     1.979V     1.731V     2.243V
461ps     1.982V     1.731V     1.982V
520ps     1.907V     1.731V     1.376V
615ps     1.349V     1.685V     168.2mV
717ps     237.4mV    1.285V     17.25mV
822ps     25.81mV    383.7mV    3.113mV
920ps     5.231mV    54.25mV    903.9uV
1.223ns   280.9uV    851.8uV    149.2uV
50ns      58.57uV    -8.068uV   23.24uV
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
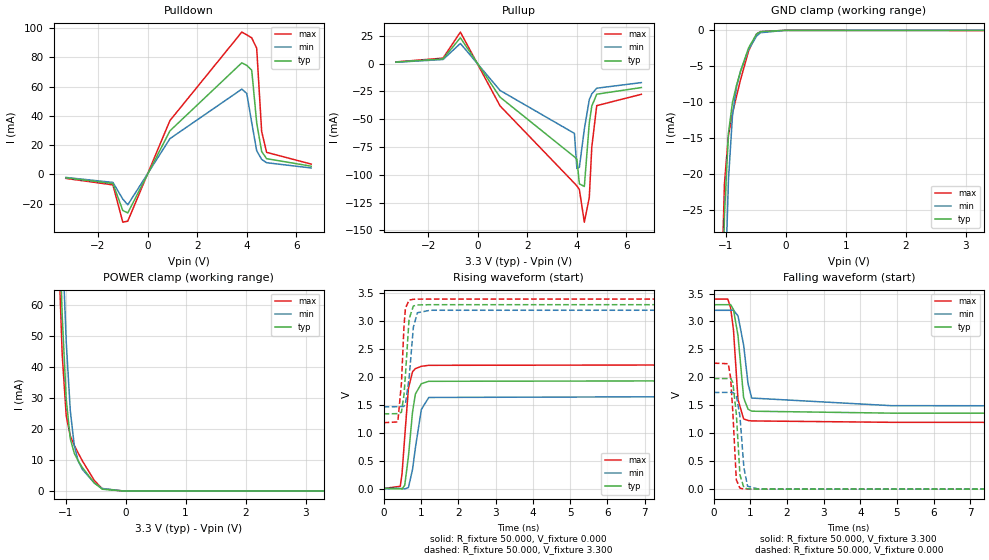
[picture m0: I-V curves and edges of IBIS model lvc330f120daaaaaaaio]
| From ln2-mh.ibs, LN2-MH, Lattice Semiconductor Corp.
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|   Model lvc330f120daaaaaaaio
[Model] lvc330f120daaaaaaaio
Model_type I/O
Polarity   Non-Inverting
Enable   Active-Low
Vinl =  0.800V
Vinh =  2.000V
Vmeas =  1.650V
Cref =  0.0F
Rref =  1.000M
Vref =  0.0V
C_comp   2.000pF   1.500pF   2.500pF
[Temperature Range]   25.000   0.125k   -40.000
[Voltage Range]   3.300V   3.200V   3.400V
[C Comp Corner]
C_comp   2.000pF   1.500pF   2.500pF
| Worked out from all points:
|   slope of the pulldown table from 0 to 0.495 V, typ, clamps not added: 26.7 ohm
|   slope of the pullup table from 0 to 0.495 V, typ, clamps not added: 26.6 ohm
|   GND clamp passes 1 mA (typ) near -0.53 V on its own axis
|   POWER clamp passes 1 mA (typ) near -0.42 V on its own axis
|   rising waveform, R_fixture 50.000, V_fixture 0.000: 20-80 % time 178ps typ, 223ps min, 149ps max; typ from 0 V to 1.98 V
|   rising waveform, R_fixture 50.000, V_fixture 3.300: 20-80 % time 111ps typ, 132ps min, 94.9ps max; typ from 1.34 V to 3.3 V
|   falling waveform, R_fixture 50.000, V_fixture 3.300: 20-80 % time 156ps typ, 194ps min, 134ps max; typ from 3.3 V to 1.34 V
|   falling waveform, R_fixture 50.000, V_fixture 0.000: 20-80 % time 110ps typ, 126ps min, 99.6ps max; typ from 1.98 V to 0 V
[Pulldown]
|Voltage   I(typ)   I(min)   I(max)
-3.3V     -2.338mA   -2.07mA    -2.72mA
-1.4V     -6.255mA   -5.479mA   -7.174mA
-1V       -24.68mA   -16.89mA   -32.68mA
-800mV    -26.36mA   -20.79mA   -31.98mA
900mV     29.78mA    24.44mA    36.81mA
3.8V      76.32mA    58.31mA    97.33mA
4V        74.56mA    55.35mA    95.44mA
4.2V      71.28mA    35.37mA    93.37mA
4.4V      35.32mA    16.17mA    86.3mA
4.6V      15.66mA    10.32mA    29.41mA
4.8V      10.76mA    7.99mA     15.09mA
6.6V      5.607mA    4.39mA     7.049mA
[Pullup]
|Voltage   I(typ)   I(min)   I(max)
-3.3V     1.282mA    1.143mA    1.472mA
-1.4V     4.186mA    3.591mA    4.84mA
-700mV    23.18mA    18.05mA    28.26mA
900mV     -30.23mA   -24.18mA   -38.08mA
3.9V      -83.87mA   -62.79mA   -107.6mA
4V        -85.93mA   -94.38mA   -110mA
4.1V      -108.1mA   -93.22mA   -113.3mA
4.3V      -110.5mA   -58.97mA   -142.6mA
4.5V      -53.45mA   -32.44mA   -120.4mA
4.6V      -38.35mA   -27.31mA   -75.26mA
4.8V      -27.55mA   -22.18mA   -37.83mA
6.6V      -21.59mA   -17.13mA   -27.66mA
[GND_clamp]
|Voltage   I(typ)   I(min)   I(max)
-3.3V     -1.861A    -1.855A    -1.868A
-1.089V   -50.83mA   -68.22mA   -41.81mA
-1.022V   -25.77mA   -39.11mA   -21.36mA
-955mV    -14.31mA   -20.77mA   -14.6mA
-888mV    -10.03mA   -11.88mA   -11.61mA
-821mV    -7.659mA   -7.903mA   -9.179mA
-754mV    -5.715mA   -5.674mA   -6.892mA
-620mV    -2.446mA   -2.677mA   -2.886mA
-486mV    -500.9uA   -793.7uA   -505.5uA
-419mV    -184.7uA   -329.9uA   -181.9uA
-17mV     -4.77uA    -4.625uA   -5.541uA
3.3V      -213nA     0A         -30.51uA
[POWER_clamp]
|Voltage   I(typ)   I(min)   I(max)
-3.266V   2.002A     2.005A     2.003A
-1.122V   95.85mA    122.4mA    80.77mA
-1.055V   56.44mA    81.14mA    43.86mA
-988mV    29.49mA    48.07mA    24.19mA
-921mV    16.88mA    26.01mA    17.76mA
-854mV    12.16mA    14.63mA    14.72mA
-787mV    9.627mA    9.57mA     12.17mA
-720mV    7.572mA    6.968mA    9.725mA
-519mV    2.543mA    2.542mA    3.339mA
-385mV    550.4uA    786uA      665.7uA
-50mV     13.15uA    11.69uA    15.71uA
3.3V      0A         0A         30.92uA
[Ramp]
| variable   typ   min   max
dV/dt_r   1.214/0.178n   1.062/0.223n   1.381/0.149n
dV/dt_f   1.203/0.157n   1.064/0.195n   1.360/0.134n
R_load = 50.000
[Rising Waveform]
R_fixture = 50.000
V_fixture = 0.000
V_fixture_min = 0.000
V_fixture_max = 0.000
|  time   V(typ)   V(min)   V(max)
0s        58.57uV    -8.068uV   23.24uV
446ps     -2.058mV   -294.3uV   40.25mV
492ps     -11.74mV   -19.33uV   258.1mV
566ps     60.83mV    -7.219mV   933.4mV
664ps     572mV      16.1mV     1.797V
774ps     1.37V      340.6mV    2.094V
852ps     1.698V     734.7mV    2.152V
1.011ns   1.881V     1.419V     2.193V
1.21ns    1.924V     1.634V     2.211V
50ns      1.979V     1.73V      2.254V
[Rising Waveform]
R_fixture = 50.000
V_fixture = 3.300
V_fixture_min = 3.200
V_fixture_max = 3.400
|  time   V(typ)   V(min)   V(max)
0s        1.339V     1.466V     1.181V
380ps     1.344V     1.469V     1.195V
477ps     1.368V     1.472V     1.893V
545ps     1.68V      1.473V     2.908V
584ps     2.032V     1.522V     3.234V
681ps     3.039V     1.973V     3.381V
797ps     3.275V     2.894V     3.396V
905ps     3.294V     3.154V     3.398V
1.245ns   3.299V     3.199V     3.4V
50ns      3.3V       3.2V       3.4V
[Falling Waveform]
R_fixture = 50.000
V_fixture = 3.300
V_fixture_min = 3.200
V_fixture_max = 3.400
|  time   V(typ)   V(min)   V(max)
0s        3.3V       3.2V       3.4V
383ps     3.3V       3.2V       3.401V
459ps     3.303V     3.2V       3.245V
538ps     3.212V     3.202V     2.847V
661ps     2.748V     3.101V     1.601V
815ps     1.635V     2.578V     1.257V
935ps     1.432V     1.887V     1.228V
1.035ns   1.395V     1.63V      1.221V
4.84ns    1.36V      1.494V     1.196V
50ns      1.339V     1.466V     1.181V
[Falling Waveform]
R_fixture = 50.000
V_fixture = 0.000
V_fixture_min = 0.000
V_fixture_max = 0.000
|  time   V(typ)   V(min)   V(max)
0s        1.979V     1.73V      2.254V
395ps     1.979V     1.731V     2.244V
460ps     1.982V     1.731V     1.99V
519ps     1.91V      1.731V     1.391V
615ps     1.348V     1.685V     169mV
714ps     255.8mV    1.306V     18.33mV
822ps     25.76mV    385mV      3.122mV
921ps     5.147mV    53.5mV     896.4uV
1.224ns   279.3uV    844.5uV    149uV
50ns      58.57uV    -8.068uV   23.24uV
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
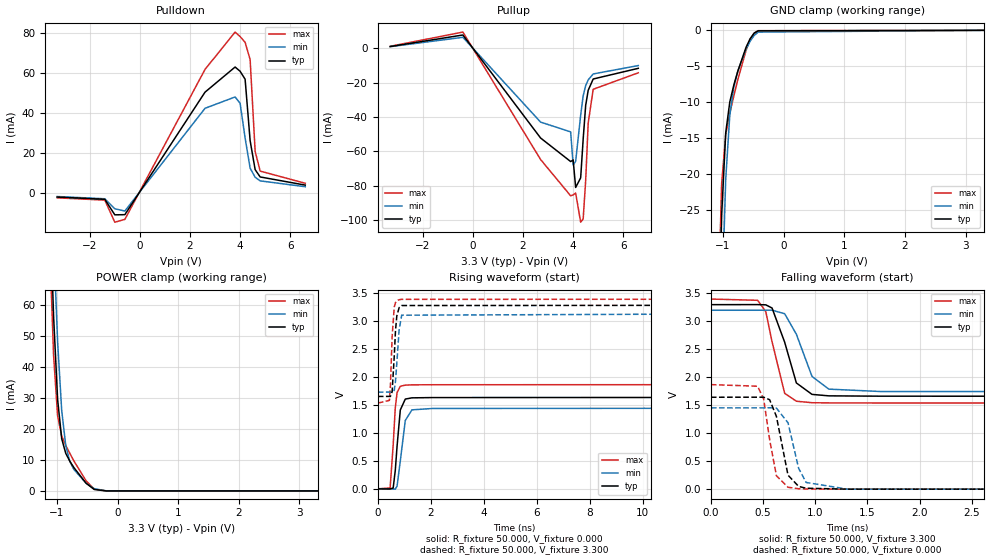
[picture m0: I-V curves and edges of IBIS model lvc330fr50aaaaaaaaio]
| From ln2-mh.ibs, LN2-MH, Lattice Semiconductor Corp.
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|   Model lvc330fr50aaaaaaaaio
[Model] lvc330fr50aaaaaaaaio
Model_type I/O
Polarity   Non-Inverting
Enable   Active-Low
Vinl =  0.800V
Vinh =  2.000V
Vmeas =  1.650V
Cref =  0.0F
Rref =  1.000M
Vref =  0.0V
C_comp   2.000pF   1.500pF   2.500pF
[Temperature Range]   25.000   0.125k   -40.000
[Voltage Range]   3.300V   3.200V   3.400V
[C Comp Corner]
C_comp   2.000pF   1.500pF   2.500pF
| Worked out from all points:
|   slope of the pulldown table from 0 to 0.495 V, typ, clamps not added: 49.7 ohm
|   slope of the pullup table from 0 to 0.495 V, typ, clamps not added: 49.7 ohm
|   GND clamp passes 1 mA (typ) near -0.54 V on its own axis
|   POWER clamp passes 1 mA (typ) near -0.43 V on its own axis
|   rising waveform, R_fixture 50.000, V_fixture 0.000: 20-80 % time 162ps typ, 210ps min, 134ps max; typ from 0 V to 1.64 V
|   rising waveform, R_fixture 50.000, V_fixture 3.300: 20-80 % time 109ps typ, 133ps min, 89.4ps max; typ from 1.66 V to 3.3 V
|   falling waveform, R_fixture 50.000, V_fixture 3.300: 20-80 % time 135ps typ, 173ps min, 115ps max; typ from 3.3 V to 1.66 V
|   falling waveform, R_fixture 50.000, V_fixture 0.000: 20-80 % time 97.5ps typ, 113ps min, 87.9ps max; typ from 1.64 V to 0 V
[Pulldown]
|Voltage   I(typ)   I(min)   I(max)
-3.3V     -1.987mA   -1.721mA   -2.37mA
-1.4V     -3.103mA   -2.837mA   -3.517mA
-1V       -10.87mA   -7.842mA   -14.55mA
-600mV    -10.79mA   -8.969mA   -13.15mA
2.6V      50.46mA    42.38mA    61.83mA
3.8V      63.01mA    48.05mA    80.48mA
4V        60.9mA     44.88mA    78.25mA
4.2V      56.9mA     27.47mA    75.35mA
4.4V      26.2mA     12.44mA    66.73mA
4.6V      11.72mA    7.921mA    20.84mA
4.8V      8.067mA    6.104mA    10.99mA
6.6V      3.982mA    3.187mA    4.9mA
[Pullup]
|Voltage   I(typ)   I(min)   I(max)
-3.3V     936.9uA    844uA      1.078mA
-400mV    7.638mA    6.288mA    9.328mA
2.7V      -52.19mA   -42.95mA   -64.68mA
3.9V      -65.87mA   -48.65mA   -85.78mA
4V        -64.94mA   -67.79mA   -85.26mA
4.1V      -80.91mA   -65.79mA   -84.16mA
4.3V      -75.33mA   -38.93mA   -101.1mA
4.4V      -52.83mA   -27.68mA   -99.22mA
4.5V      -33.23mA   -21.78mA   -76.83mA
4.6V      -24.51mA   -18.44mA   -43.56mA
4.8V      -17.92mA   -14.99mA   -23.89mA
6.6V      -11.72mA   -10.11mA   -14.32mA
[GND_clamp]
|Voltage   I(typ)   I(min)   I(max)
-3.3V     -1.861A    -1.855A    -1.868A
-1.089V   -50.81mA   -68.2mA    -41.77mA
-1.022V   -25.74mA   -39.08mA   -21.31mA
-955mV    -14.26mA   -20.73mA   -14.54mA
-888mV    -9.982mA   -11.84mA   -11.55mA
-821mV    -7.603mA   -7.856mA   -9.113mA
-754mV    -5.655mA   -5.623mA   -6.821mA
-620mV    -2.371mA   -2.616mA   -2.797mA
-553mV    -1.172mA   -1.518mA   -1.313mA
-486mV    -396.2uA   -716.4uA   -376.4uA
-419mV    -71.95uA   -244.9uA   -42.84uA
3.3V      0A         0A         0A
[POWER_clamp]
|Voltage   I(typ)   I(min)   I(max)
-3.266V   2.002A     2.005A     2.003A
-1.122V   95.84mA    122.3mA    80.75mA
-1.055V   56.42mA    81.13mA    43.84mA
-988mV    29.46mA    48.05mA    24.15mA
-921mV    16.84mA    25.99mA    17.71mA
-854mV    12.12mA    14.6mA     14.67mA
-787mV    9.585mA    9.535mA    12.12mA
-720mV    7.529mA    6.931mA    9.676mA
-519mV    2.487mA    2.496mA    3.276mA
-385mV    477.3uA    731.6uA    579.8uA
-184mV    1.009uA    11.15uA    276.7nA
3.3V      0A         0A         0A
[Ramp]
| variable   typ   min   max
dV/dt_r   1.007/0.162n   0.891/0.210n   1.145/0.134n
dV/dt_f   1.007/0.136n   0.899/0.175n   1.141/0.115n
R_load = 50.000
[Rising Waveform]
R_fixture = 50.000
V_fixture = 0.000
V_fixture_min = 0.000
V_fixture_max = 0.000
|  time   V(typ)   V(min)   V(max)
0s        2.509uV    9.592uV    933.5nV
465ps     -3.098mV   -222.5uV   15.94mV
580ps     16.37mV    -4.456mV   784.6mV
659ps     328mV      -6.076mV   1.449V
727ps     763.8mV    49.51mV    1.724V
849ps     1.413V     499.3mV    1.837V
1.037ns   1.608V     1.225V     1.858V
1.288ns   1.63V      1.415V     1.863V
2.076ns   1.635V     1.44V      1.865V
50ns      1.644V     1.454V     1.87V
[Rising Waveform]
R_fixture = 50.000
V_fixture = 3.300
V_fixture_min = 3.200
V_fixture_max = 3.400
|  time   V(typ)   V(min)   V(max)
0s        1.655V     1.732V     1.536V
437ps     1.656V     1.733V     1.584V
475ps     1.655V     1.733V     1.844V
541ps     1.74V      1.733V     2.733V
620ps     2.373V     1.766V     3.256V
667ps     2.833V     1.925V     3.336V
717ps     3.098V     2.248V     3.37V
805ps     3.247V     2.852V     3.389V
902ps     3.284V     3.111V     3.395V
50ns      3.3V       3.2V       3.4V
[Falling Waveform]
R_fixture = 50.000
V_fixture = 3.300
V_fixture_min = 3.200
V_fixture_max = 3.400
|  time   V(typ)   V(min)   V(max)
0s        3.3V       3.2V       3.4V
448ps     3.301V     3.2V       3.378V
526ps     3.297V     3.201V     3.177V
586ps     3.24V      3.201V     2.638V
707ps     2.628V     3.138V     1.714V
819ps     1.9V       2.771V     1.573V
969ps     1.695V     2.016V     1.546V
1.13ns    1.669V     1.789V     1.543V
1.632ns   1.663V     1.746V     1.541V
50ns      1.655V     1.732V     1.536V
[Falling Waveform]
R_fixture = 50.000
V_fixture = 0.000
V_fixture_min = 0.000
V_fixture_max = 0.000
|  time   V(typ)   V(min)   V(max)
0s        1.644V     1.454V     1.87V
448ps     1.645V     1.454V     1.841V
506ps     1.644V     1.454V     1.611V
563ps     1.6V       1.456V     885.5mV
628ps     1.301V     1.45V      239.4mV
739ps     250.3mV    1.187V     34.32mV
841ps     48.88mV    371.2mV    7.285mV
913ps     16.89mV    119.6mV    2.78mV
1.307ns   261.7uV    923.5uV    150.7uV
50ns      2.509uV    9.592uV    933nV
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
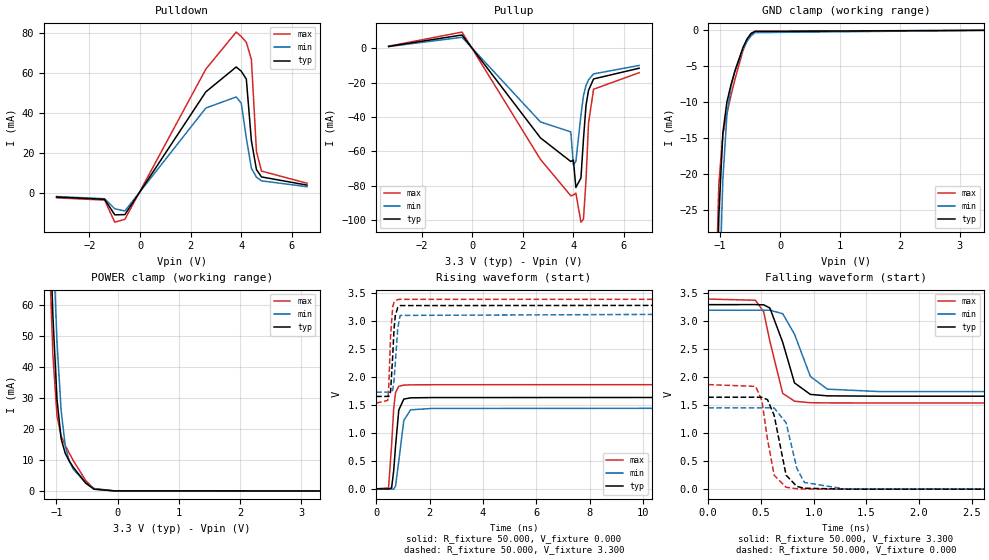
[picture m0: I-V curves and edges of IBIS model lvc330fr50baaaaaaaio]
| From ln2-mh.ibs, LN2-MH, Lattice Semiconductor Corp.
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|   Model lvc330fr50baaaaaaaio
[Model] lvc330fr50baaaaaaaio
Model_type I/O
Polarity   Non-Inverting
Enable   Active-Low
Vinl =  0.800V
Vinh =  2.000V
Vmeas =  1.650V
Cref =  0.0F
Rref =  1.000M
Vref =  0.0V
C_comp   2.000pF   1.500pF   2.500pF
[Temperature Range]   25.000   0.125k   -40.000
[Voltage Range]   3.300V   3.200V   3.400V
[C Comp Corner]
C_comp   2.000pF   1.500pF   2.500pF
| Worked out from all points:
|   slope of the pulldown table from 0 to 0.495 V, typ, clamps not added: 49.7 ohm
|   slope of the pullup table from 0 to 0.495 V, typ, clamps not added: 50.2 ohm
|   GND clamp passes 1 mA (typ) near -0.53 V on its own axis
|   POWER clamp passes 1 mA (typ) near -0.42 V on its own axis
|   rising waveform, R_fixture 50.000, V_fixture 0.000: 20-80 % time 162ps typ, 210ps min, 134ps max; typ from 0 V to 1.64 V
|   rising waveform, R_fixture 50.000, V_fixture 3.300: 20-80 % time 109ps typ, 133ps min, 89.4ps max; typ from 1.66 V to 3.3 V
|   falling waveform, R_fixture 50.000, V_fixture 3.300: 20-80 % time 135ps typ, 173ps min, 115ps max; typ from 3.3 V to 1.66 V
|   falling waveform, R_fixture 50.000, V_fixture 0.000: 20-80 % time 97.5ps typ, 113ps min, 87.9ps max; typ from 1.64 V to 0 V
[Pulldown]
|Voltage   I(typ)   I(min)   I(max)
-3.3V     -1.986mA   -1.719mA   -2.369mA
-1.4V     -3.1mA     -2.834mA   -3.514mA
-1V       -10.86mA   -7.831mA   -14.54mA
-600mV    -10.75mA   -8.931mA   -13.11mA
2.6V      50.55mA    42.47mA    61.92mA
3.8V      62.96mA    48.01mA    80.39mA
4V        60.86mA    44.85mA    78.2mA
4.2V      56.87mA    27.45mA    75.3mA
4.4V      26.18mA    12.43mA    66.69mA
4.6V      11.72mA    7.915mA    20.83mA
4.8V      8.062mA    6.099mA    10.99mA
6.6V      3.979mA    3.185mA    4.897mA
[Pullup]
|Voltage   I(typ)   I(min)   I(max)
-3.3V     934.3uA    841.6uA    1.075mA
-400mV    7.568mA    6.235mA    9.245mA
2.7V      -52.1mA    -42.86mA   -64.59mA
3.9V      -65.83mA   -48.62mA   -85.71mA
4V        -64.91mA   -67.77mA   -85.22mA
4.1V      -80.89mA   -65.78mA   -84.13mA
4.3V      -75.32mA   -38.93mA   -101mA
4.4V      -52.83mA   -27.68mA   -99.21mA
4.5V      -33.23mA   -21.77mA   -76.82mA
4.6V      -24.51mA   -18.44mA   -43.55mA
4.8V      -17.92mA   -14.99mA   -23.89mA
6.6V      -11.71mA   -10.11mA   -14.32mA
[GND_clamp]
|Voltage   I(typ)   I(min)   I(max)
-3.3V     -1.861A    -1.855A    -1.868A
-1.089V   -50.81mA   -68.21mA   -41.78mA
-1.022V   -25.75mA   -39.09mA   -21.32mA
-955mV    -14.27mA   -20.74mA   -14.55mA
-888mV    -9.999mA   -11.85mA   -11.57mA
-821mV    -7.623mA   -7.877mA   -9.132mA
-754mV    -5.679mA   -5.648mA   -6.844mA
-620mV    -2.407mA   -2.651mA   -2.831mA
-553mV    -1.221mA   -1.563mA   -1.361mA
-486mV    -463.6uA   -775.1uA   -445.5uA
-419mV    -157.8uA   -320.2uA   -132.1uA
3.4V      0A         0A         0A
[POWER_clamp]
|Voltage   I(typ)   I(min)   I(max)
-3.266V   2.002A     2.005A     2.003A
-1.122V   95.85mA    122.4mA    80.77mA
-1.055V   56.44mA    81.14mA    43.86mA
-988mV    29.49mA    48.07mA    24.19mA
-921mV    16.88mA    26.01mA    17.76mA
-854mV    12.16mA    14.63mA    14.72mA
-787mV    9.627mA    9.57mA     12.17mA
-720mV    7.572mA    6.968mA    9.725mA
-519mV    2.543mA    2.542mA    3.339mA
-385mV    550.4uA    786uA      665.7uA
-50mV     13.15uA    11.69uA    15.71uA
3.3V      0A         0A         0A
[Ramp]
| variable   typ   min   max
dV/dt_r   1.007/0.162n   0.891/0.210n   1.145/0.134n
dV/dt_f   1.007/0.136n   0.899/0.175n   1.141/0.115n
R_load = 50.000
[Rising Waveform]
R_fixture = 50.000
V_fixture = 0.000
V_fixture_min = 0.000
V_fixture_max = 0.000
|  time   V(typ)   V(min)   V(max)
0s        2.51uV     9.59uV     935nV
465ps     -3.098mV   -222.5uV   15.94mV
580ps     16.38mV    -4.456mV   784.6mV
659ps     328.3mV    -6.076mV   1.449V
727ps     764.2mV    49.51mV    1.724V
849ps     1.413V     499.3mV    1.837V
1.037ns   1.608V     1.225V     1.858V
1.289ns   1.63V      1.415V     1.863V
2.076ns   1.635V     1.44V      1.865V
50ns      1.644V     1.454V     1.87V
[Rising Waveform]
R_fixture = 50.000
V_fixture = 3.300
V_fixture_min = 3.200
V_fixture_max = 3.400
|  time   V(typ)   V(min)   V(max)
0s        1.655V     1.732V     1.536V
437ps     1.656V     1.733V     1.584V
475ps     1.655V     1.733V     1.844V
541ps     1.74V      1.733V     2.733V
621ps     2.383V     1.768V     3.26V
670ps     2.855V     1.94V      3.339V
717ps     3.098V     2.248V     3.37V
811ps     3.251V     2.881V     3.39V
899ps     3.283V     3.107V     3.395V
50ns      3.3V       3.2V       3.4V
[Falling Waveform]
R_fixture = 50.000
V_fixture = 3.300
V_fixture_min = 3.200
V_fixture_max = 3.400
|  time   V(typ)   V(min)   V(max)
0s        3.3V       3.2V       3.4V
447ps     3.301V     3.2V       3.379V
526ps     3.297V     3.201V     3.175V
585ps     3.241V     3.201V     2.646V
707ps     2.626V     3.138V     1.713V
819ps     1.9V       2.771V     1.573V
969ps     1.695V     2.017V     1.546V
1.13ns    1.669V     1.789V     1.543V
1.621ns   1.663V     1.746V     1.541V
50ns      1.655V     1.732V     1.536V
[Falling Waveform]
R_fixture = 50.000
V_fixture = 0.000
V_fixture_min = 0.000
V_fixture_max = 0.000
|  time   V(typ)   V(min)   V(max)
0s        1.644V     1.454V     1.87V
450ps     1.645V     1.454V     1.838V
509ps     1.643V     1.454V     1.585V
563ps     1.6V       1.456V     884.7mV
626ps     1.319V     1.451V     248.7mV
739ps     250.3mV    1.187V     34.3mV
841ps     48.88mV    371.2mV    7.287mV
913ps     16.89mV    119.6mV    2.778mV
1.307ns   261.7uV    923.5uV    150.6uV
50ns      2.51uV     9.59uV     934.5nV
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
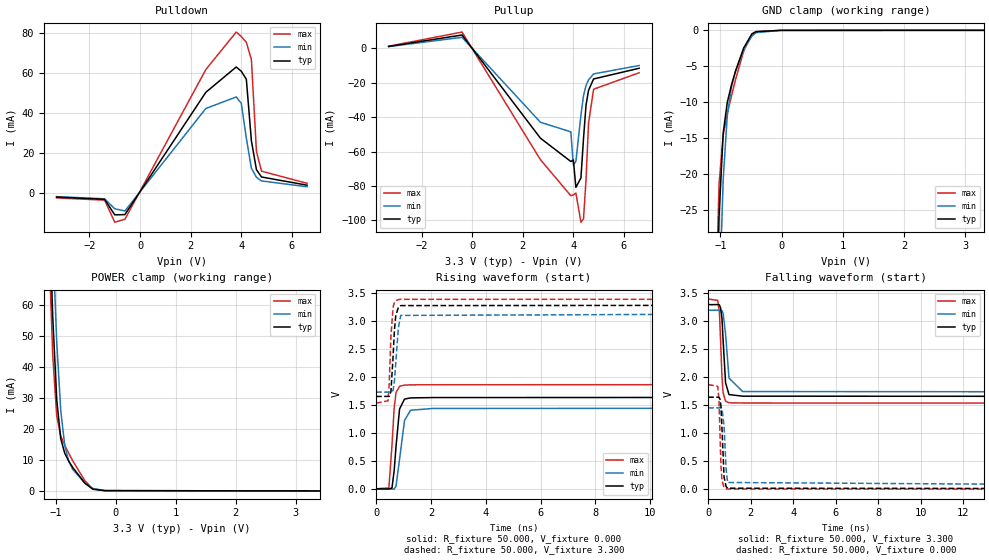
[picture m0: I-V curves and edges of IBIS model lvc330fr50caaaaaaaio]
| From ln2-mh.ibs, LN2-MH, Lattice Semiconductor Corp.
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|   Model lvc330fr50caaaaaaaio
[Model] lvc330fr50caaaaaaaio
Model_type I/O
Polarity   Non-Inverting
Enable   Active-Low
Vinl =  0.800V
Vinh =  2.000V
Vmeas =  1.650V
Cref =  0.0F
Rref =  1.000M
Vref =  0.0V
C_comp   2.000pF   1.500pF   2.500pF
[Temperature Range]   25.000   0.125k   -40.000
[Voltage Range]   3.300V   3.200V   3.400V
[C Comp Corner]
C_comp   2.000pF   1.500pF   2.500pF
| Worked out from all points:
|   slope of the pulldown table from 0 to 0.495 V, typ, clamps not added: 50.1 ohm
|   slope of the pullup table from 0 to 0.495 V, typ, clamps not added: 49.7 ohm
|   GND clamp passes 1 mA (typ) near -0.53 V on its own axis
|   POWER clamp passes 1 mA (typ) near -0.42 V on its own axis
|   rising waveform, R_fixture 50.000, V_fixture 0.000: 20-80 % time 162ps typ, 210ps min, 134ps max; typ from 0 V to 1.64 V
|   rising waveform, R_fixture 50.000, V_fixture 3.300: 20-80 % time 109ps typ, 133ps min, 89.3ps max; typ from 1.66 V to 3.3 V
|   falling waveform, R_fixture 50.000, V_fixture 3.300: 20-80 % time 136ps typ, 173ps min, 115ps max; typ from 3.3 V to 1.66 V
|   falling waveform, R_fixture 50.000, V_fixture 0.000: 20-80 % time 97.5ps typ, 113ps min, 87.9ps max; typ from 1.64 V to 0 V
[Pulldown]
|Voltage   I(typ)   I(min)   I(max)
-3.3V     -1.981mA   -1.715mA   -2.363mA
-1.4V     -3.092mA   -2.827mA   -3.505mA
-1V       -10.83mA   -7.812mA   -14.5mA
-600mV    -10.71mA   -8.906mA   -13.05mA
2.6V      50.37mA    42.28mA    61.73mA
3.8V      62.98mA    48.02mA    80.42mA
4V        60.88mA    44.86mA    78.23mA
4.2V      56.89mA    27.46mA    75.33mA
4.4V      26.19mA    12.43mA    66.72mA
4.6V      11.72mA    7.919mA    20.84mA
4.8V      8.066mA    6.102mA    10.99mA
6.6V      3.981mA    3.186mA    4.9mA
[Pullup]
|Voltage   I(typ)   I(min)   I(max)
-3.3V     936.4uA    843uA      1.077mA
-400mV    7.579mA    6.233mA    9.271mA
2.7V      -52.28mA   -43.04mA   -64.77mA
3.9V      -65.8mA    -48.59mA   -85.65mA
4V        -64.88mA   -67.74mA   -85.16mA
4.1V      -80.85mA   -65.75mA   -84.08mA
4.3V      -75.29mA   -38.91mA   -101mA
4.4V      -52.81mA   -27.67mA   -99.16mA
4.5V      -33.21mA   -21.77mA   -76.79mA
4.6V      -24.5mA    -18.43mA   -43.54mA
4.8V      -17.91mA   -14.99mA   -23.88mA
6.6V      -11.71mA   -10.11mA   -14.32mA
[GND_clamp]
|Voltage   I(typ)   I(min)   I(max)
-3.3V     -1.861A    -1.855A    -1.868A
-1.089V   -50.83mA   -68.22mA   -41.81mA
-1.022V   -25.77mA   -39.11mA   -21.36mA
-955mV    -14.31mA   -20.77mA   -14.6mA
-888mV    -10.03mA   -11.88mA   -11.61mA
-821mV    -7.659mA   -7.903mA   -9.179mA
-754mV    -5.715mA   -5.674mA   -6.892mA
-620mV    -2.446mA   -2.677mA   -2.886mA
-486mV    -500.9uA   -793.7uA   -505.5uA
-419mV    -184.7uA   -329.9uA   -181.9uA
-17mV     -4.77uA    -4.625uA   -5.541uA
3.3V      0A         0A         0A
[POWER_clamp]
|Voltage   I(typ)   I(min)   I(max)
-3.266V   2.002A     2.005A     2.003A
-1.122V   95.84mA    122.3mA    80.75mA
-1.055V   56.43mA    81.13mA    43.84mA
-988mV    29.47mA    48.06mA    24.16mA
-921mV    16.85mA    26mA       17.72mA
-854mV    12.14mA    14.62mA    14.69mA
-787mV    9.602mA    9.553mA    12.13mA
-720mV    7.548mA    6.952mA    9.693mA
-519mV    2.524mA    2.533mA    3.308mA
-385mV    541.5uA    790.3uA    641.3uA
-184mV    92.6uA     101.7uA    92.48uA
3.4V      0A         0A         0A
[Ramp]
| variable   typ   min   max
dV/dt_r   1.007/0.162n   0.891/0.210n   1.145/0.134n
dV/dt_f   1.007/0.136n   0.899/0.175n   1.141/0.116n
R_load = 50.000
[Rising Waveform]
R_fixture = 50.000
V_fixture = 0.000
V_fixture_min = 0.000
V_fixture_max = 0.000
|  time   V(typ)   V(min)   V(max)
0s        87.51uV    -11.28uV   36.1uV
465ps     -3.014mV   -243.4uV   15.98mV
579ps     14.83mV    -4.405mV   775.5mV
659ps     327.1mV    -6.097mV   1.449V
727ps     763mV      49.49mV    1.724V
856ps     1.431V     531.3mV    1.839V
1.037ns   1.608V     1.225V     1.858V
1.257ns   1.629V     1.408V     1.863V
2.066ns   1.635V     1.44V      1.865V
50ns      1.644V     1.454V     1.87V
[Rising Waveform]
R_fixture = 50.000
V_fixture = 3.300
V_fixture_min = 3.200
V_fixture_max = 3.400
|  time   V(typ)   V(min)   V(max)
0s        1.655V     1.732V     1.536V
435ps     1.656V     1.733V     1.578V
479ps     1.656V     1.733V     1.889V
541ps     1.74V      1.733V     2.734V
621ps     2.384V     1.768V     3.26V
670ps     2.855V     1.94V      3.339V
717ps     3.098V     2.249V     3.37V
811ps     3.251V     2.881V     3.39V
899ps     3.283V     3.107V     3.395V
50ns      3.3V       3.2V       3.4V
[Falling Waveform]
R_fixture = 50.000
V_fixture = 3.300
V_fixture_min = 3.200
V_fixture_max = 3.400
|  time   V(typ)   V(min)   V(max)
0s        3.3V       3.2V       3.4V
448ps     3.301V     3.2V       3.378V
527ps     3.296V     3.201V     3.172V
585ps     3.24V      3.201V     2.649V
649ps     3.051V     3.191V     2.002V
703ps     2.659V     3.143V     1.725V
818ps     1.903V     2.777V     1.573V
979ps     1.692V     1.987V     1.545V
1.622ns   1.663V     1.746V     1.541V
50ns      1.655V     1.732V     1.536V
[Falling Waveform]
R_fixture = 50.000
V_fixture = 0.000
V_fixture_min = 0.000
V_fixture_max = 0.000
|  time   V(typ)   V(min)   V(max)
0s        1.644V     1.454V     1.87V
448ps     1.645V     1.454V     1.841V
506ps     1.644V     1.454V     1.611V
557ps     1.61V      1.456V     977.7mV
602ps     1.477V     1.454V     407.7mV
653ps     1.049V     1.436V     150.3mV
747ps     217.7mV    1.136V     30.2mV
841ps     48.96mV    371.1mV    7.336mV
913ps     16.97mV    119.5mV    2.816mV
50ns      87.51uV    -11.28uV   36.1uV
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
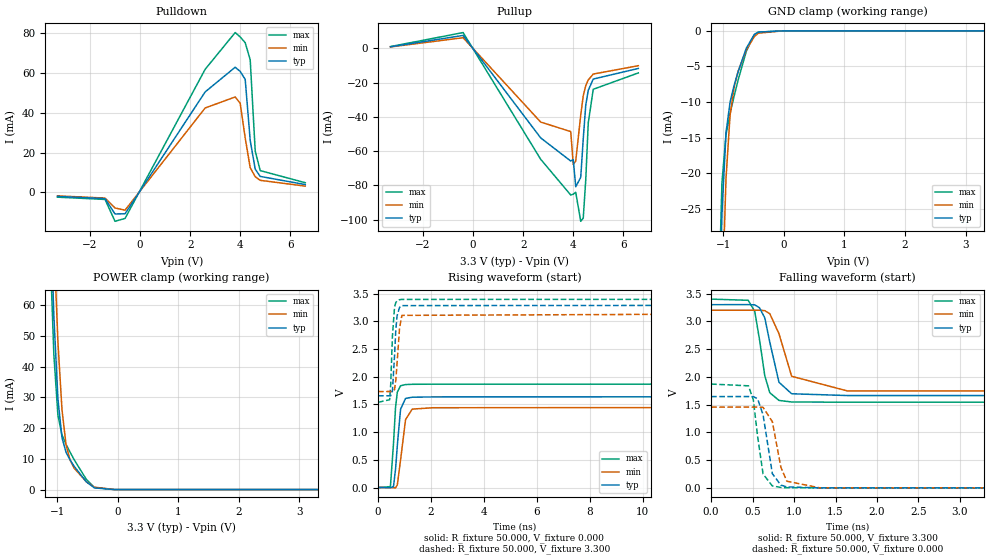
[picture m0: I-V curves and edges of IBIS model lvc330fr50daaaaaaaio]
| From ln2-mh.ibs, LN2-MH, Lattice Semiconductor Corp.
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|   Model lvc330fr50daaaaaaaio
[Model] lvc330fr50daaaaaaaio
Model_type I/O
Polarity   Non-Inverting
Enable   Active-Low
Vinl =  0.800V
Vinh =  2.000V
Vmeas =  1.650V
Cref =  0.0F
Rref =  1.000M
Vref =  0.0V
C_comp   2.000pF   1.500pF   2.500pF
[Temperature Range]   25.000   0.125k   -40.000
[Voltage Range]   3.300V   3.200V   3.400V
[C Comp Corner]
C_comp   2.000pF   1.500pF   2.500pF
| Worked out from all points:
|   slope of the pulldown table from 0 to 0.495 V, typ, clamps not added: 50.1 ohm
|   slope of the pullup table from 0 to 0.495 V, typ, clamps not added: 50.2 ohm
|   GND clamp passes 1 mA (typ) near -0.53 V on its own axis
|   POWER clamp passes 1 mA (typ) near -0.42 V on its own axis
|   rising waveform, R_fixture 50.000, V_fixture 0.000: 20-80 % time 162ps typ, 210ps min, 134ps max; typ from 0 V to 1.64 V
|   rising waveform, R_fixture 50.000, V_fixture 3.300: 20-80 % time 109ps typ, 133ps min, 89.4ps max; typ from 1.66 V to 3.3 V
|   falling waveform, R_fixture 50.000, V_fixture 3.300: 20-80 % time 135ps typ, 173ps min, 115ps max; typ from 3.3 V to 1.66 V
|   falling waveform, R_fixture 50.000, V_fixture 0.000: 20-80 % time 97.6ps typ, 113ps min, 87.9ps max; typ from 1.64 V to 0 V
[Pulldown]
|Voltage   I(typ)   I(min)   I(max)
-3.3V     -1.981mA   -1.715mA   -2.363mA
-1.4V     -3.092mA   -2.827mA   -3.505mA
-1V       -10.83mA   -7.812mA   -14.5mA
-600mV    -10.71mA   -8.906mA   -13.05mA
2.6V      50.55mA    42.47mA    61.92mA
3.8V      62.96mA    48.01mA    80.39mA
4V        60.86mA    44.85mA    78.2mA
4.2V      56.87mA    27.45mA    75.3mA
4.4V      26.18mA    12.43mA    66.69mA
4.6V      11.72mA    7.915mA    20.83mA
4.8V      8.062mA    6.099mA    10.99mA
6.6V      3.979mA    3.185mA    4.897mA
[Pullup]
|Voltage   I(typ)   I(min)   I(max)
-3.3V     934.3uA    841.6uA    1.075mA
-400mV    7.568mA    6.235mA    9.245mA
2.7V      -52.28mA   -43.04mA   -64.77mA
3.9V      -65.8mA    -48.59mA   -85.65mA
4V        -64.88mA   -67.74mA   -85.16mA
4.1V      -80.85mA   -65.75mA   -84.08mA
4.3V      -75.29mA   -38.91mA   -101mA
4.4V      -52.81mA   -27.67mA   -99.16mA
4.5V      -33.21mA   -21.77mA   -76.79mA
4.6V      -24.5mA    -18.43mA   -43.54mA
4.8V      -17.91mA   -14.99mA   -23.88mA
6.6V      -11.71mA   -10.11mA   -14.32mA
[GND_clamp]
|Voltage   I(typ)   I(min)   I(max)
-3.3V     -1.861A    -1.855A    -1.868A
-1.089V   -50.83mA   -68.22mA   -41.81mA
-1.022V   -25.77mA   -39.11mA   -21.36mA
-955mV    -14.31mA   -20.77mA   -14.6mA
-888mV    -10.03mA   -11.88mA   -11.61mA
-821mV    -7.659mA   -7.903mA   -9.179mA
-754mV    -5.715mA   -5.674mA   -6.892mA
-620mV    -2.446mA   -2.677mA   -2.886mA
-486mV    -500.9uA   -793.7uA   -505.5uA
-419mV    -184.7uA   -329.9uA   -181.9uA
-17mV     -4.77uA    -4.625uA   -5.541uA
3.3V      -213nA     0A         -30.51uA
[POWER_clamp]
|Voltage   I(typ)   I(min)   I(max)
-3.266V   2.002A     2.005A     2.003A
-1.122V   95.85mA    122.4mA    80.77mA
-1.055V   56.44mA    81.14mA    43.86mA
-988mV    29.49mA    48.07mA    24.19mA
-921mV    16.88mA    26.01mA    17.76mA
-854mV    12.16mA    14.63mA    14.72mA
-787mV    9.627mA    9.57mA     12.17mA
-720mV    7.572mA    6.968mA    9.725mA
-519mV    2.543mA    2.542mA    3.339mA
-385mV    550.4uA    786uA      665.7uA
-50mV     13.15uA    11.69uA    15.71uA
3.3V      0A         0A         30.92uA
[Ramp]
| variable   typ   min   max
dV/dt_r   1.007/0.162n   0.891/0.210n   1.145/0.134n
dV/dt_f   1.007/0.136n   0.899/0.175n   1.141/0.116n
R_load = 50.000
[Rising Waveform]
R_fixture = 50.000
V_fixture = 0.000
V_fixture_min = 0.000
V_fixture_max = 0.000
|  time   V(typ)   V(min)   V(max)
0s        87.51uV    -11.28uV   36.1uV
465ps     -3.013mV   -243.6uV   15.98mV
580ps     16.45mV    -4.472mV   784.6mV
659ps     328.1mV    -6.093mV   1.449V
727ps     763.9mV    49.44mV    1.724V
849ps     1.413V     499.1mV    1.837V
1.037ns   1.608V     1.225V     1.858V
1.288ns   1.63V      1.415V     1.863V
2.077ns   1.635V     1.44V      1.865V
50ns      1.644V     1.454V     1.87V
[Rising Waveform]
R_fixture = 50.000
V_fixture = 3.300
V_fixture_min = 3.200
V_fixture_max = 3.400
|  time   V(typ)   V(min)   V(max)
0s        1.655V     1.732V     1.538V
437ps     1.656V     1.733V     1.585V
476ps     1.656V     1.733V     1.856V
541ps     1.74V      1.733V     2.733V
621ps     2.382V     1.768V     3.26V
668ps     2.839V     1.93V      3.337V
717ps     3.098V     2.248V     3.37V
811ps     3.251V     2.88V      3.39V
899ps     3.283V     3.107V     3.395V
50ns      3.3V       3.2V       3.4V
[Falling Waveform]
R_fixture = 50.000
V_fixture = 3.300
V_fixture_min = 3.200
V_fixture_max = 3.400
|  time   V(typ)   V(min)   V(max)
0s        3.3V       3.2V       3.4V
447ps     3.301V     3.2V       3.379V
526ps     3.297V     3.201V     3.178V
583ps     3.244V     3.201V     2.673V
647ps     3.062V     3.192V     2.019V
707ps     2.626V     3.138V     1.715V
818ps     1.903V     2.777V     1.575V
971ps     1.695V     2.01V      1.547V
1.644ns   1.663V     1.746V     1.543V
50ns      1.655V     1.732V     1.538V
[Falling Waveform]
R_fixture = 50.000
V_fixture = 0.000
V_fixture_min = 0.000
V_fixture_max = 0.000
|  time   V(typ)   V(min)   V(max)
0s        1.644V     1.454V     1.87V
450ps     1.645V     1.454V     1.838V
509ps     1.643V     1.454V     1.585V
560ps     1.605V     1.456V     930.5mV
626ps     1.319V     1.451V     248.7mV
738ps     255.3mV    1.193V     34.9mV
841ps     49.02mV    371.1mV    7.322mV
913ps     17mV       119.5mV    2.813mV
1.309ns   344.1uV    885.3uV    185uV
50ns      87.51uV    -11.28uV   36.1uV
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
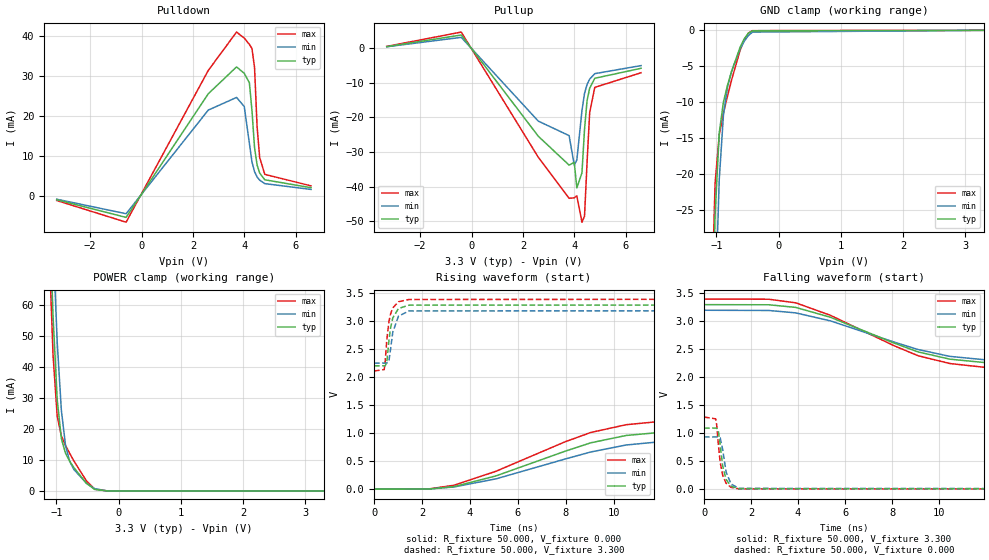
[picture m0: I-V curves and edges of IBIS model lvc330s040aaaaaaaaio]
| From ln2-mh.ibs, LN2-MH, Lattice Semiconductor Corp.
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|   Model lvc330s040aaaaaaaaio
[Model] lvc330s040aaaaaaaaio
Model_type I/O
Polarity   Non-Inverting
Enable   Active-Low
Vinl =  0.800V
Vinh =  2.000V
Vmeas =  1.650V
Cref =  0.0F
Rref =  1.000M
Vref =  0.0V
C_comp   2.000pF   1.500pF   2.500pF
[Temperature Range]   25.000   0.125k   -40.000
[Voltage Range]   3.300V   3.200V   3.400V
[C Comp Corner]
C_comp   2.000pF   1.500pF   2.500pF
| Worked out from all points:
|   slope of the pulldown table from 0 to 0.495 V, typ, clamps not added: 98.5 ohm
|   slope of the pullup table from 0 to 0.495 V, typ, clamps not added: 98.9 ohm
|   GND clamp passes 1 mA (typ) near -0.54 V on its own axis
|   POWER clamp passes 1 mA (typ) near -0.43 V on its own axis
|   rising waveform, R_fixture 50.000, V_fixture 0.000: 20-80 % time 4.49ns typ, 4.81ns min, 4.49ns max; typ from 0 V to 1.09 V
|   rising waveform, R_fixture 50.000, V_fixture 3.300: 20-80 % time 224ps typ, 234ps min, 215ps max; typ from 2.21 V to 3.3 V
|   falling waveform, R_fixture 50.000, V_fixture 3.300: 20-80 % time 4.01ns typ, 4.25ns min, 4.02ns max; typ from 3.3 V to 2.21 V
|   falling waveform, R_fixture 50.000, V_fixture 0.000: 20-80 % time 232ps typ, 243ps min, 225ps max; typ from 1.09 V to 0 V
[Pulldown]
|Voltage   I(typ)   I(min)   I(max)
-3.3V     -991.1uA   -858.3uA   -1.183mA
-600mV    -5.406mA   -4.489mA   -6.6mA
2.6V      25.49mA    21.41mA    31.32mA
3.7V      32.19mA    24.56mA    40.89mA
4V        30.59mA    22.3mA     39.39mA
4.2V      28.23mA    13.08mA    37.81mA
4.3V      21.31mA    8.47mA     36.8mA
4.4V      12.1mA     6.034mA    32.08mA
4.5V      7.681mA    4.709mA    17.27mA
4.6V      5.686mA    3.907mA    9.552mA
4.8V      3.997mA    3.033mA    5.35mA
6.6V      2.008mA    1.58mA     2.473mA
[Pullup]
|Voltage   I(typ)   I(min)   I(max)
-3.3V     467.7uA    422.2uA    537.6uA
-400mV    3.822mA    3.145mA    4.669mA
2.6V      -25.45mA   -21.08mA   -31.53mA
3.8V      -33.81mA   -25.27mA   -43.4mA
4V        -33mA      -33.77mA   -43.26mA
4.1V      -40.39mA   -32.36mA   -42.69mA
4.3V      -36.05mA   -18.05mA   -50.31mA
4.4V      -23.44mA   -13.06mA   -48.55mA
4.5V      -15.1mA    -10.46mA   -32.86mA
4.6V      -11.58mA   -8.931mA   -18.68mA
4.8V      -8.69mA    -7.351mA   -11.32mA
6.6V      -5.804mA   -5.021mA   -7.09mA
[GND_clamp]
|Voltage   I(typ)   I(min)   I(max)
-3.3V     -1.861A    -1.855A    -1.868A
-1.089V   -50.81mA   -68.2mA    -41.77mA
-1.022V   -25.74mA   -39.08mA   -21.31mA
-955mV    -14.26mA   -20.73mA   -14.54mA
-888mV    -9.982mA   -11.84mA   -11.55mA
-821mV    -7.603mA   -7.856mA   -9.113mA
-754mV    -5.655mA   -5.623mA   -6.821mA
-620mV    -2.371mA   -2.616mA   -2.797mA
-553mV    -1.172mA   -1.518mA   -1.313mA
-486mV    -396.2uA   -716.4uA   -376.4uA
-419mV    -71.95uA   -244.9uA   -42.84uA
3.3V      0A         0A         0A
[POWER_clamp]
|Voltage   I(typ)   I(min)   I(max)
-3.266V   2.002A     2.005A     2.003A
-1.122V   95.84mA    122.3mA    80.75mA
-1.055V   56.42mA    81.13mA    43.84mA
-988mV    29.46mA    48.05mA    24.15mA
-921mV    16.84mA    25.99mA    17.71mA
-854mV    12.12mA    14.6mA     14.67mA
-787mV    9.585mA    9.535mA    12.12mA
-720mV    7.529mA    6.931mA    9.676mA
-519mV    2.487mA    2.496mA    3.276mA
-385mV    477.3uA    731.6uA    579.8uA
-184mV    1.009uA    11.15uA    276.7nA
3.3V      0A         0A         0A
[Ramp]
| variable   typ   min   max
dV/dt_r   0.669/4.516n   0.572/4.829n   0.790/4.506n
dV/dt_f   0.670/4.024n   0.580/4.263n   0.788/4.032n
R_load = 50.000
[Rising Waveform]
R_fixture = 50.000
V_fixture = 0.000
V_fixture_min = 0.000
V_fixture_max = 0.000
|  time   V(typ)   V(min)   V(max)
0s        3.936uV    16.32uV    1.484uV
2.284ns   2.209mV    3.74mV     4.675mV
3.334ns   45.07mV    38.45mV    69.58mV
5.101ns   238.4mV    185.4mV    321.7mV
7.974ns   678mV      538.4mV    846.5mV
9.052ns   829.3mV    665.4mV    1.014V
10.53ns   960.5mV    790.2mV    1.153V
12.26ns   1.027V     860.8mV    1.224V
18.88ns   1.087V     928.3mV    1.284V
50ns      1.092V     934.2mV    1.29V
[Rising Waveform]
R_fixture = 50.000
V_fixture = 3.300
V_fixture_min = 3.200
V_fixture_max = 3.400
|  time   V(typ)   V(min)   V(max)
0s        2.206V     2.254V     2.113V
425ps     2.206V     2.255V     2.139V
466ps     2.207V     2.255V     2.282V
532ps     2.262V     2.255V     2.663V
621ps     2.649V     2.29V      2.992V
690ps     2.883V     2.503V     3.132V
783ps     3.061V     2.808V     3.241V
1.02ns    3.231V     3.094V     3.352V
1.46ns    3.291V     3.187V     3.393V
50ns      3.3V       3.2V       3.4V
[Falling Waveform]
R_fixture = 50.000
V_fixture = 3.300
V_fixture_min = 3.200
V_fixture_max = 3.400
|  time   V(typ)   V(min)   V(max)
0s        3.3V       3.2V       3.4V
2.756ns   3.298V     3.196V     3.397V
3.9ns     3.251V     3.153V     3.333V
5.376ns   3.075V     3.01V      3.11V
8.085ns   2.614V     2.631V     2.566V
9.106ns   2.455V     2.498V     2.387V
10.46ns   2.325V     2.375V     2.247V
12.03ns   2.261V     2.311V     2.175V
18.67ns   2.209V     2.259V     2.116V
50ns      2.206V     2.254V     2.113V
[Falling Waveform]
R_fixture = 50.000
V_fixture = 0.000
V_fixture_min = 0.000
V_fixture_max = 0.000
|  time   V(typ)   V(min)   V(max)
0s        1.092V     934.2mV    1.29V
497ps     1.092V     933.9mV    1.258V
538ps     1.091V     934.1mV    1.151V
605ps     1.054V     934.4mV    820.6mV
689ps     785.8mV    919.3mV    476.7mV
795ps     409.5mV    704.9mV    248.4mV
939ps     174mV      306.9mV    106.7mV
1.149ns   52.54mV    92.26mV    32.14mV
1.488ns   8.089mV    14.19mV    5.041mV
50ns      3.936uV    16.32uV    1.484uV
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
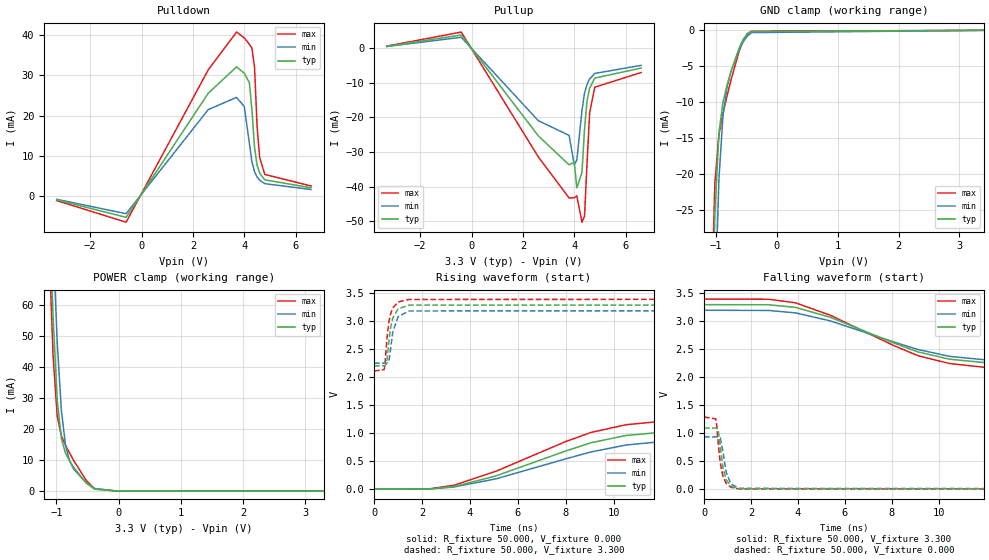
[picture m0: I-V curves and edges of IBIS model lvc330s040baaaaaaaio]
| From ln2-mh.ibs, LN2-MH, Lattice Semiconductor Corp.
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|   Model lvc330s040baaaaaaaio
[Model] lvc330s040baaaaaaaio
Model_type I/O
Polarity   Non-Inverting
Enable   Active-Low
Vinl =  0.800V
Vinh =  2.000V
Vmeas =  1.650V
Cref =  0.0F
Rref =  1.000M
Vref =  0.0V
C_comp   2.000pF   1.500pF   2.500pF
[Temperature Range]   25.000   0.125k   -40.000
[Voltage Range]   3.300V   3.200V   3.400V
[C Comp Corner]
C_comp   2.000pF   1.500pF   2.500pF
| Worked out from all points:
|   slope of the pulldown table from 0 to 0.495 V, typ, clamps not added: 98.5 ohm
|   slope of the pullup table from 0 to 0.495 V, typ, clamps not added: 101 ohm
|   GND clamp passes 1 mA (typ) near -0.53 V on its own axis
|   POWER clamp passes 1 mA (typ) near -0.42 V on its own axis
|   rising waveform, R_fixture 50.000, V_fixture 0.000: 20-80 % time 4.49ns typ, 4.81ns min, 4.49ns max; typ from 0 V to 1.09 V
|   rising waveform, R_fixture 50.000, V_fixture 3.300: 20-80 % time 224ps typ, 234ps min, 215ps max; typ from 2.21 V to 3.3 V
|   falling waveform, R_fixture 50.000, V_fixture 3.300: 20-80 % time 4.01ns typ, 4.25ns min, 4.03ns max; typ from 3.3 V to 2.21 V
|   falling waveform, R_fixture 50.000, V_fixture 0.000: 20-80 % time 232ps typ, 243ps min, 225ps max; typ from 1.09 V to 0 V
[Pulldown]
|Voltage   I(typ)   I(min)   I(max)
-3.3V     -989.9uA   -857uA     -1.182mA
-600mV    -5.367mA   -4.451mA   -6.562mA
2.6V      25.58mA    21.5mA     31.41mA
3.7V      32.12mA    24.52mA    40.79mA
4V        30.54mA    22.26mA    39.34mA
4.2V      28.19mA    13.06mA    37.76mA
4.3V      21.28mA    8.459mA    36.76mA
4.4V      12.09mA    6.025mA    32.05mA
4.5V      7.672mA    4.702mA    17.25mA
4.6V      5.679mA    3.902mA    9.541mA
4.8V      3.992mA    3.029mA    5.344mA
6.6V      2.005mA    1.578mA    2.47mA
[Pullup]
|Voltage   I(typ)   I(min)   I(max)
-3.3V     465.1uA    419.8uA    534.8uA
-400mV    3.751mA    3.091mA    4.586mA
2.6V      -25.36mA   -20.99mA   -31.43mA
3.8V      -33.75mA   -25.23mA   -43.3mA
4V        -32.97mA   -33.75mA   -43.22mA
4.1V      -40.37mA   -32.35mA   -42.66mA
4.3V      -36.04mA   -18.04mA   -50.29mA
4.4V      -23.43mA   -13.05mA   -48.54mA
4.5V      -15.09mA   -10.46mA   -32.85mA
4.6V      -11.58mA   -8.928mA   -18.67mA
4.8V      -8.688mA   -7.349mA   -11.32mA
6.6V      -5.803mA   -5.02mA    -7.088mA
[GND_clamp]
|Voltage   I(typ)   I(min)   I(max)
-3.3V     -1.861A    -1.855A    -1.868A
-1.089V   -50.81mA   -68.21mA   -41.78mA
-1.022V   -25.75mA   -39.09mA   -21.32mA
-955mV    -14.27mA   -20.74mA   -14.55mA
-888mV    -9.999mA   -11.85mA   -11.57mA
-821mV    -7.623mA   -7.877mA   -9.132mA
-754mV    -5.679mA   -5.648mA   -6.844mA
-620mV    -2.407mA   -2.651mA   -2.831mA
-553mV    -1.221mA   -1.563mA   -1.361mA
-486mV    -463.6uA   -775.1uA   -445.5uA
-419mV    -157.8uA   -320.2uA   -132.1uA
3.4V      0A         0A         0A
[POWER_clamp]
|Voltage   I(typ)   I(min)   I(max)
-3.266V   2.002A     2.005A     2.003A
-1.122V   95.85mA    122.4mA    80.77mA
-1.055V   56.44mA    81.14mA    43.86mA
-988mV    29.49mA    48.07mA    24.19mA
-921mV    16.88mA    26.01mA    17.76mA
-854mV    12.16mA    14.63mA    14.72mA
-787mV    9.627mA    9.57mA     12.17mA
-720mV    7.572mA    6.968mA    9.725mA
-519mV    2.543mA    2.542mA    3.339mA
-385mV    550.4uA    786uA      665.7uA
-50mV     13.15uA    11.69uA    15.71uA
3.3V      0A         0A         0A
[Ramp]
| variable   typ   min   max
dV/dt_r   0.669/4.512n   0.572/4.827n   0.790/4.513n
dV/dt_f   0.670/4.020n   0.580/4.263n   0.788/4.047n
R_load = 50.000
[Rising Waveform]
R_fixture = 50.000
V_fixture = 0.000
V_fixture_min = 0.000
V_fixture_max = 0.000
|  time   V(typ)   V(min)   V(max)
0s        3.936uV    16.32uV    1.485uV
2.284ns   2.215mV    3.74mV     4.675mV
3.332ns   44.96mV    38.34mV    69.38mV
5.101ns   238.5mV    185.4mV    321.7mV
7.984ns   679.5mV    539.7mV    848.2mV
9.054ns   829.6mV    665.7mV    1.014V
10.53ns   960.5mV    790.2mV    1.153V
12.26ns   1.027V     860.8mV    1.224V
18.88ns   1.087V     928.3mV    1.284V
50ns      1.092V     934.2mV    1.29V
[Rising Waveform]
R_fixture = 50.000
V_fixture = 3.300
V_fixture_min = 3.200
V_fixture_max = 3.400
|  time   V(typ)   V(min)   V(max)
0s        2.206V     2.254V     2.113V
424ps     2.206V     2.255V     2.138V
464ps     2.206V     2.255V     2.271V
532ps     2.262V     2.255V     2.662V
621ps     2.649V     2.29V      2.992V
692ps     2.888V     2.511V     3.135V
782ps     3.059V     2.806V     3.24V
1.003ns   3.224V     3.084V     3.347V
1.46ns    3.291V     3.187V     3.393V
50ns      3.3V       3.2V       3.4V
[Falling Waveform]
R_fixture = 50.000
V_fixture = 3.300
V_fixture_min = 3.200
V_fixture_max = 3.400
|  time   V(typ)   V(min)   V(max)
0s        3.3V       3.2V       3.4V
2.757ns   3.298V     3.196V     3.397V
3.897ns   3.251V     3.153V     3.333V
5.376ns   3.075V     3.01V      3.111V
8.088ns   2.614V     2.631V     2.567V
9.107ns   2.455V     2.498V     2.388V
10.46ns   2.324V     2.375V     2.247V
12.04ns   2.26V      2.311V     2.175V
18.71ns   2.209V     2.259V     2.116V
50ns      2.206V     2.254V     2.113V
[Falling Waveform]
R_fixture = 50.000
V_fixture = 0.000
V_fixture_min = 0.000
V_fixture_max = 0.000
|  time   V(typ)   V(min)   V(max)
0s        1.092V     934.2mV    1.29V
497ps     1.092V     933.9mV    1.258V
538ps     1.091V     934.1mV    1.151V
605ps     1.054V     934.4mV    820.4mV
690ps     781.5mV    918.9mV    473.6mV
804ps     387.5mV    674.8mV    235.3mV
944ps     169mV      298.4mV    103.6mV
1.15ns    52.24mV    91.83mV    31.96mV
1.489ns   8.046mV    14.12mV    5.015mV
50ns      3.936uV    16.32uV    1.485uV
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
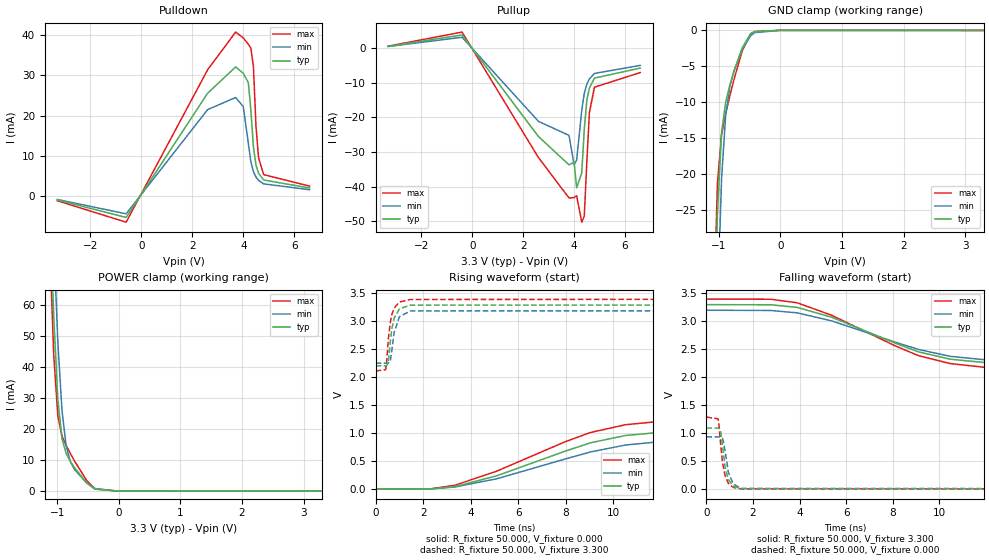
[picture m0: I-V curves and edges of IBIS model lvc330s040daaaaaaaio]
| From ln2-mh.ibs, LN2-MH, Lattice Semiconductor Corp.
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|   Model lvc330s040daaaaaaaio
[Model] lvc330s040daaaaaaaio
Model_type I/O
Polarity   Non-Inverting
Enable   Active-Low
Vinl =  0.800V
Vinh =  2.000V
Vmeas =  1.650V
Cref =  0.0F
Rref =  1.000M
Vref =  0.0V
C_comp   2.000pF   1.500pF   2.500pF
[Temperature Range]   25.000   0.125k   -40.000
[Voltage Range]   3.300V   3.200V   3.400V
[C Comp Corner]
C_comp   2.000pF   1.500pF   2.500pF
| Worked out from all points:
|   slope of the pulldown table from 0 to 0.495 V, typ, clamps not added: 100 ohm
|   slope of the pullup table from 0 to 0.495 V, typ, clamps not added: 101 ohm
|   GND clamp passes 1 mA (typ) near -0.53 V on its own axis
|   POWER clamp passes 1 mA (typ) near -0.42 V on its own axis
|   rising waveform, R_fixture 50.000, V_fixture 0.000: 20-80 % time 4.49ns typ, 4.81ns min, 4.49ns max; typ from 0 V to 1.09 V
|   rising waveform, R_fixture 50.000, V_fixture 3.300: 20-80 % time 224ps typ, 235ps min, 215ps max; typ from 2.21 V to 3.3 V
|   falling waveform, R_fixture 50.000, V_fixture 3.300: 20-80 % time 4.01ns typ, 4.25ns min, 4.03ns max; typ from 3.3 V to 2.21 V
|   falling waveform, R_fixture 50.000, V_fixture 0.000: 20-80 % time 232ps typ, 243ps min, 225ps max; typ from 1.09 V to 0 V
[Pulldown]
|Voltage   I(typ)   I(min)   I(max)
-3.3V     -985.1uA   -853.1uA   -1.176mA
-600mV    -5.328mA   -4.426mA   -6.507mA
2.6V      25.58mA    21.5mA     31.41mA
3.7V      32.12mA    24.52mA    40.79mA
4V        30.54mA    22.26mA    39.34mA
4.2V      28.19mA    13.06mA    37.76mA
4.3V      21.28mA    8.459mA    36.76mA
4.4V      12.09mA    6.025mA    32.05mA
4.5V      7.672mA    4.702mA    17.25mA
4.6V      5.679mA    3.902mA    9.541mA
4.8V      3.992mA    3.029mA    5.344mA
6.6V      2.005mA    1.578mA    2.47mA
[Pullup]
|Voltage   I(typ)   I(min)   I(max)
-3.3V     465.1uA    419.8uA    534.8uA
-400mV    3.751mA    3.091mA    4.586mA
2.6V      -25.54mA   -21.17mA   -31.62mA
3.8V      -33.71mA   -25.21mA   -43.26mA
4V        -32.94mA   -33.73mA   -43.17mA
4.1V      -40.33mA   -32.32mA   -42.61mA
4.3V      -36.01mA   -18.03mA   -50.25mA
4.4V      -23.41mA   -13.04mA   -48.5mA
4.5V      -15.08mA   -10.45mA   -32.83mA
4.6V      -11.57mA   -8.921mA   -18.66mA
4.8V      -8.681mA   -7.343mA   -11.31mA
6.6V      -5.798mA   -5.016mA   -7.082mA
[GND_clamp]
|Voltage   I(typ)   I(min)   I(max)
-3.3V     -1.861A    -1.855A    -1.868A
-1.089V   -50.83mA   -68.22mA   -41.81mA
-1.022V   -25.77mA   -39.11mA   -21.36mA
-955mV    -14.31mA   -20.77mA   -14.6mA
-888mV    -10.03mA   -11.88mA   -11.61mA
-821mV    -7.659mA   -7.903mA   -9.179mA
-754mV    -5.715mA   -5.674mA   -6.892mA
-620mV    -2.446mA   -2.677mA   -2.886mA
-486mV    -500.9uA   -793.7uA   -505.5uA
-419mV    -184.7uA   -329.9uA   -181.9uA
-17mV     -4.77uA    -4.625uA   -5.541uA
3.3V      -213nA     0A         -30.51uA
[POWER_clamp]
|Voltage   I(typ)   I(min)   I(max)
-3.266V   2.002A     2.005A     2.003A
-1.122V   95.85mA    122.4mA    80.77mA
-1.055V   56.44mA    81.14mA    43.86mA
-988mV    29.49mA    48.07mA    24.19mA
-921mV    16.88mA    26.01mA    17.76mA
-854mV    12.16mA    14.63mA    14.72mA
-787mV    9.627mA    9.57mA     12.17mA
-720mV    7.572mA    6.968mA    9.725mA
-519mV    2.543mA    2.542mA    3.339mA
-385mV    550.4uA    786uA      665.7uA
-50mV     13.15uA    11.69uA    15.71uA
3.3V      0A         0A         30.92uA
[Ramp]
| variable   typ   min   max
dV/dt_r   0.669/4.516n   0.572/4.825n   0.790/4.513n
dV/dt_f   0.670/4.023n   0.580/4.263n   0.788/4.034n
R_load = 50.000
[Rising Waveform]
R_fixture = 50.000
V_fixture = 0.000
V_fixture_min = 0.000
V_fixture_max = 0.000
|  time   V(typ)   V(min)   V(max)
0s        117uV      -10.83uV   49.78uV
2.286ns   2.358mV    3.743mV    4.766mV
3.335ns   45.28mV    38.47mV    69.71mV
5.101ns   238.6mV    185.3mV    321.7mV
7.982ns   679.3mV    539.4mV    847.8mV
9.052ns   829.4mV    665.4mV    1.014V
10.53ns   960.5mV    790.1mV    1.153V
12.27ns   1.027V     860.8mV    1.224V
18.88ns   1.087V     928.3mV    1.284V
50ns      1.092V     934.2mV    1.29V
[Rising Waveform]
R_fixture = 50.000
V_fixture = 3.300
V_fixture_min = 3.200
V_fixture_max = 3.400
|  time   V(typ)   V(min)   V(max)
0s        2.206V     2.254V     2.113V
424ps     2.206V     2.255V     2.138V
464ps     2.206V     2.255V     2.271V
533ps     2.265V     2.255V     2.668V
621ps     2.648V     2.29V      2.992V
691ps     2.886V     2.508V     3.134V
782ps     3.059V     2.806V     3.24V
1.003ns   3.224V     3.084V     3.347V
1.46ns    3.291V     3.187V     3.393V
50ns      3.3V       3.2V       3.4V
[Falling Waveform]
R_fixture = 50.000
V_fixture = 3.300
V_fixture_min = 3.200
V_fixture_max = 3.400
|  time   V(typ)   V(min)   V(max)
0s        3.3V       3.2V       3.4V
2.757ns   3.298V     3.196V     3.397V
3.897ns   3.251V     3.153V     3.333V
5.376ns   3.075V     3.01V      3.11V
8.087ns   2.614V     2.631V     2.566V
9.106ns   2.455V     2.499V     2.387V
10.46ns   2.325V     2.376V     2.247V
12.03ns   2.261V     2.311V     2.175V
18.68ns   2.209V     2.259V     2.116V
50ns      2.206V     2.254V     2.113V
[Falling Waveform]
R_fixture = 50.000
V_fixture = 0.000
V_fixture_min = 0.000
V_fixture_max = 0.000
|  time   V(typ)   V(min)   V(max)
0s        1.092V     934.2mV    1.29V
497ps     1.092V     933.9mV    1.258V
538ps     1.091V     934.1mV    1.15V
605ps     1.054V     934.4mV    819.1mV
689ps     785.8mV    919.3mV    475.9mV
800ps     397.3mV    688mV      240.8mV
939ps     174.1mV    306.9mV    106.5mV
1.149ns   52.65mV    92.24mV    32.14mV
1.488ns   8.201mV    14.16mV    5.082mV
50ns      117uV      -10.83uV   49.78uV
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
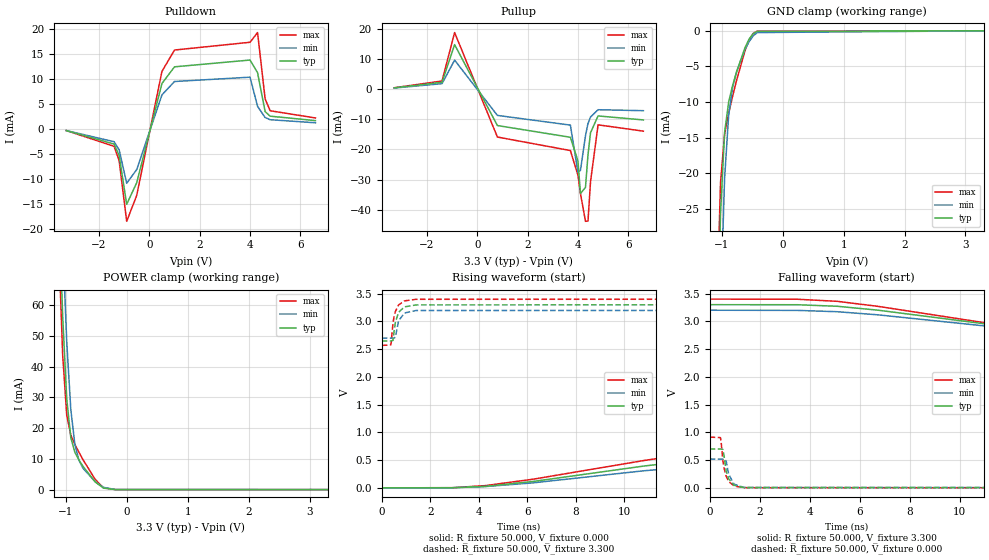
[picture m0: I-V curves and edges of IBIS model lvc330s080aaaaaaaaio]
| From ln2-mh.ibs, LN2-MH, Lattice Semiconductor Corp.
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|   Model lvc330s080aaaaaaaaio
[Model] lvc330s080aaaaaaaaio
Model_type I/O
Polarity   Non-Inverting
Enable   Active-Low
Vinl =  0.800V
Vinh =  2.000V
Vmeas =  1.650V
Cref =  0.0F
Rref =  1.000M
Vref =  0.0V
C_comp   2.000pF   1.500pF   2.500pF
[Temperature Range]   25.000   0.125k   -40.000
[Voltage Range]   3.300V   3.200V   3.400V
[C Comp Corner]
C_comp   2.000pF   1.500pF   2.500pF
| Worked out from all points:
|   slope of the pulldown table from 0 to 0.495 V, typ, clamps not added: 55.2 ohm
|   slope of the pullup table from 0 to 0.495 V, typ, clamps not added: 54.7 ohm
|   GND clamp passes 1 mA (typ) near -0.54 V on its own axis
|   POWER clamp passes 1 mA (typ) near -0.43 V on its own axis
|   rising waveform, R_fixture 50.000, V_fixture 0.000: 20-80 % time 7.6ns typ, 7.24ns min, 8.19ns max; typ from 0 V to 0.699 V
|   rising waveform, R_fixture 50.000, V_fixture 3.300: 20-80 % time 204ps typ, 208ps min, 200ps max; typ from 2.64 V to 3.3 V
|   falling waveform, R_fixture 50.000, V_fixture 3.300: 20-80 % time 7.46ns typ, 7.07ns min, 7.97ns max; typ from 3.3 V to 2.64 V
|   falling waveform, R_fixture 50.000, V_fixture 0.000: 20-80 % time 206ps typ, 210ps min, 203ps max; typ from 0.699 V to 0 V
[Pulldown]
|Voltage   I(typ)   I(min)   I(max)
-3.3V     -352.1uA   -351uA     -351.1uA
-1.4V     -3.051mA   -2.583mA   -3.502mA
-1.2V     -5.34mA    -4.199mA   -6.367mA
-900mV    -15.08mA   -10.89mA   -18.49mA
-500mV    -10.76mA   -8.133mA   -13.29mA
500mV     9.048mA    6.78mA     11.47mA
1V        12.39mA    9.457mA    15.75mA
4V        13.75mA    10.32mA    17.3mA
4.3V      11.21mA    4.481mA    19.24mA
4.6V      3.439mA    2.258mA    5.994mA
4.8V      2.525mA    1.821mA    3.608mA
6.6V      1.635mA    1.206mA    2.169mA
[Pullup]
|Voltage   I(typ)   I(min)   I(max)
-3.3V     345.2uA    299uA      393uA
-1.4V     2.195mA    1.745mA    2.635mA
-900mV    14.67mA    9.541mA    18.66mA
800mV     -12.11mA   -8.762mA   -15.92mA
3.7V      -16mA      -11.97mA   -20.39mA
4V        -23.83mA   -27.6mA    -28.52mA
4.1V      -34.64mA   -26.97mA   -34.6mA
4.3V      -32.56mA   -15.49mA   -43.81mA
4.4V      -21.76mA   -11.43mA   -43.72mA
4.5V      -14.49mA   -9.284mA   -30.71mA
4.8V      -8.938mA   -6.879mA   -11.88mA
6.6V      -10.26mA   -7.195mA   -13.97mA
[GND_clamp]
|Voltage   I(typ)   I(min)   I(max)
-3.3V     -1.861A    -1.855A    -1.868A
-1.089V   -50.81mA   -68.2mA    -41.77mA
-1.022V   -25.74mA   -39.08mA   -21.31mA
-955mV    -14.26mA   -20.73mA   -14.54mA
-888mV    -9.982mA   -11.84mA   -11.55mA
-821mV    -7.603mA   -7.856mA   -9.113mA
-754mV    -5.655mA   -5.623mA   -6.821mA
-620mV    -2.371mA   -2.616mA   -2.797mA
-553mV    -1.172mA   -1.518mA   -1.313mA
-486mV    -396.2uA   -716.4uA   -376.4uA
-419mV    -71.95uA   -244.9uA   -42.84uA
3.3V      0A         0A         0A
[POWER_clamp]
|Voltage   I(typ)   I(min)   I(max)
-3.266V   2.002A     2.005A     2.003A
-1.122V   95.84mA    122.3mA    80.75mA
-1.055V   56.42mA    81.13mA    43.84mA
-988mV    29.46mA    48.05mA    24.15mA
-921mV    16.84mA    25.99mA    17.71mA
-854mV    12.12mA    14.6mA     14.67mA
-787mV    9.585mA    9.535mA    12.12mA
-720mV    7.529mA    6.931mA    9.676mA
-519mV    2.487mA    2.496mA    3.276mA
-385mV    477.3uA    731.6uA    579.8uA
-184mV    1.009uA    11.15uA    276.7nA
3.3V      0A         0A         0A
[Ramp]
| variable   typ   min   max
dV/dt_r   0.429/7.611n   0.319/7.252n   0.561/8.211n
dV/dt_f   0.403/7.463n   0.309/7.095n   0.512/7.982n
R_load = 50.000
[Rising Waveform]
R_fixture = 50.000
V_fixture = 0.000
V_fixture_min = 0.000
V_fixture_max = 0.000
|  time   V(typ)   V(min)   V(max)
0s        3.336uV    16.38uV    1.174uV
2.921ns   1.76mV     2.771mV    3.024mV
4.268ns   26.71mV    22.87mV    40.34mV
6.262ns   116.3mV    90.84mV    157mV
10.8ns    391.8mV    307mV      491.2mV
13.45ns   526.2mV    405.5mV    661.2mV
16.23ns   621.5mV    472mV      789.7mV
19.48ns   681.4mV    508.1mV    879.4mV
23.77ns   693.3mV    514.3mV    908.5mV
50ns      699mV      519.6mV    914mV
[Rising Waveform]
R_fixture = 50.000
V_fixture = 3.300
V_fixture_min = 3.200
V_fixture_max = 3.400
|  time   V(typ)   V(min)   V(max)
0s        2.644V     2.697V     2.566V
372ps     2.647V     2.698V     2.575V
388ps     2.647V     2.698V     2.609V
462ps     2.655V     2.699V     2.96V
507ps     2.809V     2.699V     3.081V
562ps     2.981V     2.714V     3.176V
692ps     3.16V      3.004V     3.294V
932ps     3.26V      3.149V     3.368V
1.414ns   3.296V     3.195V     3.397V
50ns      3.3V       3.2V       3.4V
[Falling Waveform]
R_fixture = 50.000
V_fixture = 3.300
V_fixture_min = 3.200
V_fixture_max = 3.400
|  time   V(typ)   V(min)   V(max)
0s        3.3V       3.2V       3.4V
3.509ns   3.299V     3.197V     3.398V
5.109ns   3.271V     3.173V     3.36V
6.727ns   3.201V     3.117V     3.27V
11.28ns   2.939V     2.904V     2.955V
14.02ns   2.805V     2.803V     2.792V
16.67ns   2.717V     2.741V     2.677V
19.82ns   2.662V     2.709V     2.597V
23.63ns   2.649V     2.702V     2.571V
50ns      2.644V     2.697V     2.566V
[Falling Waveform]
R_fixture = 50.000
V_fixture = 0.000
V_fixture_min = 0.000
V_fixture_max = 0.000
|  time   V(typ)   V(min)   V(max)
0s        699mV      519.6mV    914mV
430ps     698.5mV    519.2mV    905.8mV
455ps     698.7mV    519.2mV    849.1mV
529ps     691.7mV    519.2mV    491.8mV
575ps     575.8mV    519.5mV    356.6mV
659ps     305.3mV    485.8mV    210.1mV
759ps     162.7mV    245.1mV    116.1mV
975ps     46.92mV    66.8mV     33.6mV
1.37ns    5.245mV    7.555mV    3.749mV
50ns      3.336uV    16.38uV    1.174uV
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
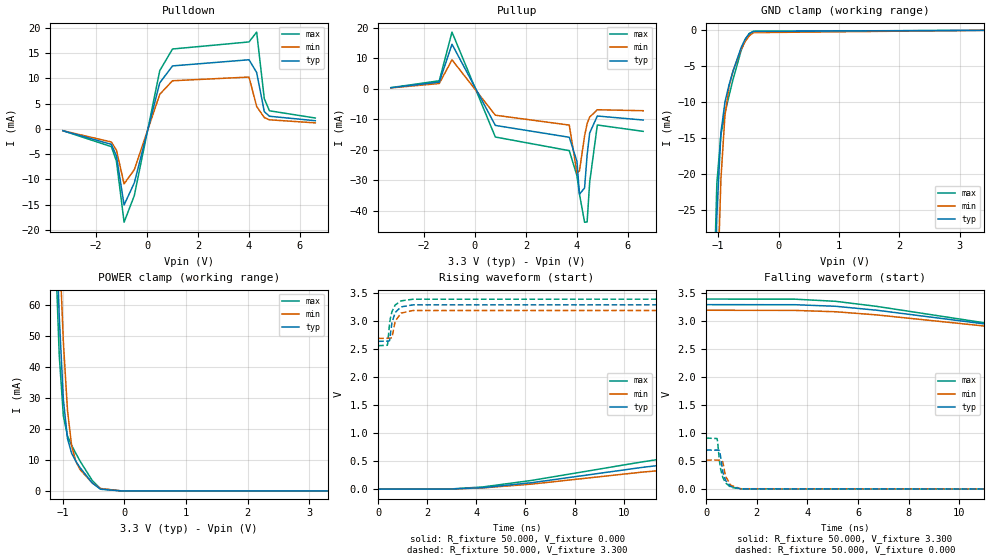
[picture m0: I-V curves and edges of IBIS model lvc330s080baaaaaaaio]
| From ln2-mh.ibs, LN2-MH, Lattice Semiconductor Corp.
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|   Model lvc330s080baaaaaaaio
[Model] lvc330s080baaaaaaaio
Model_type I/O
Polarity   Non-Inverting
Enable   Active-Low
Vinl =  0.800V
Vinh =  2.000V
Vmeas =  1.650V
Cref =  0.0F
Rref =  1.000M
Vref =  0.0V
C_comp   2.000pF   1.500pF   2.500pF
[Temperature Range]   25.000   0.125k   -40.000
[Voltage Range]   3.300V   3.200V   3.400V
[C Comp Corner]
C_comp   2.000pF   1.500pF   2.500pF
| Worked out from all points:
|   slope of the pulldown table from 0 to 0.495 V, typ, clamps not added: 55.2 ohm
|   slope of the pullup table from 0 to 0.495 V, typ, clamps not added: 55.2 ohm
|   GND clamp passes 1 mA (typ) near -0.53 V on its own axis
|   POWER clamp passes 1 mA (typ) near -0.42 V on its own axis
|   rising waveform, R_fixture 50.000, V_fixture 0.000: 20-80 % time 7.6ns typ, 7.24ns min, 8.19ns max; typ from 0 V to 0.699 V
|   rising waveform, R_fixture 50.000, V_fixture 3.300: 20-80 % time 203ps typ, 208ps min, 200ps max; typ from 2.64 V to 3.3 V
|   falling waveform, R_fixture 50.000, V_fixture 3.300: 20-80 % time 7.46ns typ, 7.07ns min, 7.97ns max; typ from 3.3 V to 2.64 V
|   falling waveform, R_fixture 50.000, V_fixture 0.000: 20-80 % time 206ps typ, 210ps min, 203ps max; typ from 0.699 V to 0 V
[Pulldown]
|Voltage   I(typ)   I(min)   I(max)
-3.3V     -350.9uA   -349.7uA   -349.9uA
-1.4V     -3.048mA   -2.58mA    -3.499mA
-1.2V     -5.336mA   -4.195mA   -6.363mA
-900mV    -15.06mA   -10.88mA   -18.47mA
-500mV    -10.7mA    -8.078mA   -13.22mA
500mV     9.141mA    6.873mA    11.56mA
1V        12.49mA    9.55mA     15.84mA
4V        13.71mA    10.28mA    17.24mA
4.3V      11.18mA    4.468mA    19.19mA
4.6V      3.432mA    2.253mA    5.984mA
4.8V      2.519mA    1.816mA    3.602mA
6.6V      1.633mA    1.204mA    2.166mA
[Pullup]
|Voltage   I(typ)   I(min)   I(max)
-3.3V     342.6uA    296.6uA    390.2uA
-1.4V     2.189mA    1.739mA    2.629mA
-900mV    14.63mA    9.513mA    18.62mA
800mV     -12.02mA   -8.67mA    -15.83mA
3.7V      -15.91mA   -11.91mA   -20.3mA
4V        -23.8mA    -27.58mA   -28.49mA
4.1V      -34.62mA   -26.95mA   -34.57mA
4.3V      -32.55mA   -15.49mA   -43.79mA
4.4V      -21.75mA   -11.42mA   -43.7mA
4.5V      -14.49mA   -9.281mA   -30.7mA
4.8V      -8.936mA   -6.876mA   -11.88mA
6.6V      -10.25mA   -7.194mA   -13.97mA
[GND_clamp]
|Voltage   I(typ)   I(min)   I(max)
-3.3V     -1.861A    -1.855A    -1.868A
-1.089V   -50.81mA   -68.21mA   -41.78mA
-1.022V   -25.75mA   -39.09mA   -21.32mA
-955mV    -14.27mA   -20.74mA   -14.55mA
-888mV    -9.999mA   -11.85mA   -11.57mA
-821mV    -7.623mA   -7.877mA   -9.132mA
-754mV    -5.679mA   -5.648mA   -6.844mA
-620mV    -2.407mA   -2.651mA   -2.831mA
-553mV    -1.221mA   -1.563mA   -1.361mA
-486mV    -463.6uA   -775.1uA   -445.5uA
-419mV    -157.8uA   -320.2uA   -132.1uA
3.4V      0A         0A         0A
[POWER_clamp]
|Voltage   I(typ)   I(min)   I(max)
-3.266V   2.002A     2.005A     2.003A
-1.122V   95.85mA    122.4mA    80.77mA
-1.055V   56.44mA    81.14mA    43.86mA
-988mV    29.49mA    48.07mA    24.19mA
-921mV    16.88mA    26.01mA    17.76mA
-854mV    12.16mA    14.63mA    14.72mA
-787mV    9.627mA    9.57mA     12.17mA
-720mV    7.572mA    6.968mA    9.725mA
-519mV    2.543mA    2.542mA    3.339mA
-385mV    550.4uA    786uA      665.7uA
-50mV     13.15uA    11.69uA    15.71uA
3.3V      0A         0A         0A
[Ramp]
| variable   typ   min   max
dV/dt_r   0.429/7.611n   0.319/7.252n   0.561/8.207n
dV/dt_f   0.403/7.484n   0.309/7.088n   0.512/7.971n
R_load = 50.000
[Rising Waveform]
R_fixture = 50.000
V_fixture = 0.000
V_fixture_min = 0.000
V_fixture_max = 0.000
|  time   V(typ)   V(min)   V(max)
0s        3.337uV    16.37uV    1.176uV
2.921ns   1.76mV     2.771mV    3.025mV
4.268ns   26.71mV    22.87mV    40.34mV
6.262ns   116.3mV    90.85mV    157mV
10.8ns    391.9mV    307mV      491.2mV
13.45ns   526.2mV    405.5mV    661.2mV
16.23ns   621.5mV    472mV      789.7mV
19.48ns   681.4mV    508.1mV    879.4mV
23.77ns   693.3mV    514.3mV    908.5mV
50ns      699mV      519.6mV    914mV
[Rising Waveform]
R_fixture = 50.000
V_fixture = 3.300
V_fixture_min = 3.200
V_fixture_max = 3.400
|  time   V(typ)   V(min)   V(max)
0s        2.644V     2.697V     2.566V
372ps     2.647V     2.698V     2.574V
388ps     2.647V     2.698V     2.608V
462ps     2.655V     2.699V     2.959V
500ps     2.778V     2.699V     3.064V
562ps     2.981V     2.714V     3.176V
692ps     3.16V      3.004V     3.294V
932ps     3.26V      3.149V     3.368V
1.414ns   3.296V     3.195V     3.397V
50ns      3.3V       3.2V       3.4V
[Falling Waveform]
R_fixture = 50.000
V_fixture = 3.300
V_fixture_min = 3.200
V_fixture_max = 3.400
|  time   V(typ)   V(min)   V(max)
0s        3.3V       3.2V       3.4V
3.506ns   3.299V     3.197V     3.398V
5.109ns   3.271V     3.173V     3.36V
6.723ns   3.201V     3.117V     3.27V
11.28ns   2.939V     2.904V     2.955V
14.02ns   2.805V     2.803V     2.792V
16.67ns   2.717V     2.741V     2.677V
19.82ns   2.662V     2.709V     2.597V
23.63ns   2.649V     2.702V     2.571V
50ns      2.644V     2.697V     2.566V
[Falling Waveform]
R_fixture = 50.000
V_fixture = 0.000
V_fixture_min = 0.000
V_fixture_max = 0.000
|  time   V(typ)   V(min)   V(max)
0s        699mV      519.6mV    914mV
430ps     698.5mV    519.2mV    905.6mV
456ps     698.7mV    519.2mV    844.1mV
527ps     693.3mV    519.2mV    497.9mV
576ps     573.2mV    519.6mV    353.6mV
659ps     306.1mV    485.8mV    209.7mV
765ps     157.3mV    235.4mV    111.9mV
970ps     48.35mV    68.69mV    34.53mV
1.37ns    5.254mV    7.555mV    3.744mV
50ns      3.337uV    16.37uV    1.176uV
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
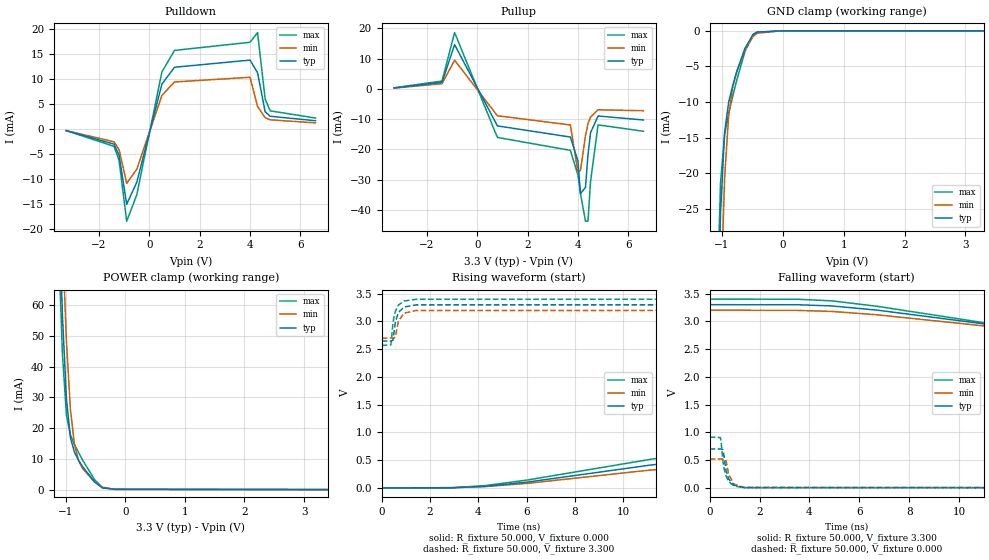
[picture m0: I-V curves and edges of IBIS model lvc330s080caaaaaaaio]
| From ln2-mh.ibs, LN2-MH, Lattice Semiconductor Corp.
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|   Model lvc330s080caaaaaaaio
[Model] lvc330s080caaaaaaaio
Model_type I/O
Polarity   Non-Inverting
Enable   Active-Low
Vinl =  0.800V
Vinh =  2.000V
Vmeas =  1.650V
Cref =  0.0F
Rref =  1.000M
Vref =  0.0V
C_comp   2.000pF   1.500pF   2.500pF
[Temperature Range]   25.000   0.125k   -40.000
[Voltage Range]   3.300V   3.200V   3.400V
[C Comp Corner]
C_comp   2.000pF   1.500pF   2.500pF
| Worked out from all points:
|   slope of the pulldown table from 0 to 0.495 V, typ, clamps not added: 55.7 ohm
|   slope of the pullup table from 0 to 0.495 V, typ, clamps not added: 54.7 ohm
|   GND clamp passes 1 mA (typ) near -0.53 V on its own axis
|   POWER clamp passes 1 mA (typ) near -0.42 V on its own axis
|   rising waveform, R_fixture 50.000, V_fixture 0.000: 20-80 % time 7.6ns typ, 7.24ns min, 8.19ns max; typ from 0 V to 0.699 V
|   rising waveform, R_fixture 50.000, V_fixture 3.300: 20-80 % time 204ps typ, 208ps min, 200ps max; typ from 2.64 V to 3.3 V
|   falling waveform, R_fixture 50.000, V_fixture 3.300: 20-80 % time 7.46ns typ, 7.08ns min, 7.97ns max; typ from 3.3 V to 2.64 V
|   falling waveform, R_fixture 50.000, V_fixture 0.000: 20-80 % time 206ps typ, 210ps min, 203ps max; typ from 0.699 V to 0 V
[Pulldown]
|Voltage   I(typ)   I(min)   I(max)
-3.3V     -346.1uA   -345.8uA   -343.9uA
-1.4V     -3.04mA    -2.573mA   -3.49mA
-1.2V     -5.324mA   -4.185mA   -6.348mA
-900mV    -15.03mA   -10.85mA   -18.43mA
-500mV    -10.66mA   -8.058mA   -13.16mA
500mV     8.96mA     6.694mA    11.38mA
1V        12.3mA     9.366mA    15.66mA
4V        13.73mA    10.3mA     17.28mA
4.3V      11.2mA     4.476mA    19.22mA
4.6V      3.437mA    2.256mA    5.992mA
4.8V      2.523mA    1.819mA    3.607mA
6.6V      1.635mA    1.206mA    2.169mA
[Pullup]
|Voltage   I(typ)   I(min)   I(max)
-3.3V     344.7uA    298uA      392.4uA
-1.4V     2.193mA    1.743mA    2.634mA
-900mV    14.66mA    9.528mA    18.65mA
800mV     -12.2mA    -8.854mA   -16.01mA
3.7V      -15.89mA   -11.89mA   -20.29mA
4V        -23.77mA   -27.55mA   -28.43mA
4.1V      -34.58mA   -26.93mA   -34.52mA
4.3V      -32.52mA   -15.47mA   -43.74mA
4.4V      -21.73mA   -11.41mA   -43.66mA
4.5V      -14.48mA   -9.273mA   -30.68mA
4.8V      -8.928mA   -6.87mA    -11.87mA
6.6V      -10.25mA   -7.19mA    -13.97mA
[GND_clamp]
|Voltage   I(typ)   I(min)   I(max)
-3.3V     -1.861A    -1.855A    -1.868A
-1.089V   -50.83mA   -68.22mA   -41.81mA
-1.022V   -25.77mA   -39.11mA   -21.36mA
-955mV    -14.31mA   -20.77mA   -14.6mA
-888mV    -10.03mA   -11.88mA   -11.61mA
-821mV    -7.659mA   -7.903mA   -9.179mA
-754mV    -5.715mA   -5.674mA   -6.892mA
-620mV    -2.446mA   -2.677mA   -2.886mA
-486mV    -500.9uA   -793.7uA   -505.5uA
-419mV    -184.7uA   -329.9uA   -181.9uA
-17mV     -4.77uA    -4.625uA   -5.541uA
3.3V      0A         0A         0A
[POWER_clamp]
|Voltage   I(typ)   I(min)   I(max)
-3.266V   2.002A     2.005A     2.003A
-1.122V   95.84mA    122.3mA    80.75mA
-1.055V   56.43mA    81.13mA    43.84mA
-988mV    29.47mA    48.06mA    24.16mA
-921mV    16.85mA    26mA       17.72mA
-854mV    12.14mA    14.62mA    14.69mA
-787mV    9.602mA    9.553mA    12.13mA
-720mV    7.548mA    6.952mA    9.693mA
-519mV    2.524mA    2.533mA    3.308mA
-385mV    541.5uA    790.3uA    641.3uA
-184mV    92.6uA     101.7uA    92.48uA
3.4V      0A         0A         0A
[Ramp]
| variable   typ   min   max
dV/dt_r   0.429/7.611n   0.319/7.245n   0.561/8.210n
dV/dt_f   0.403/7.467n   0.309/7.092n   0.512/7.971n
R_load = 50.000
[Rising Waveform]
R_fixture = 50.000
V_fixture = 0.000
V_fixture_min = 0.000
V_fixture_max = 0.000
|  time   V(typ)   V(min)   V(max)
0s        87.16uV    -5.445uV   35.24uV
2.922ns   1.846mV    2.756mV    3.069mV
4.268ns   26.77mV    22.85mV    40.38mV
6.009ns   102.6mV    80.21mV    139.9mV
11.1ns    409.2mV    320mV      512.6mV
13.8ns    540.6mV    415.6mV    680.2mV
16.61ns   631.1mV    478.6mV    803mV
19.69ns   683.1mV    508.9mV    883.3mV
23.77ns   693.3mV    514.3mV    908.5mV
50ns      699mV      519.6mV    914mV
[Rising Waveform]
R_fixture = 50.000
V_fixture = 3.300
V_fixture_min = 3.200
V_fixture_max = 3.400
|  time   V(typ)   V(min)   V(max)
0s        2.644V     2.697V     2.566V
372ps     2.647V     2.698V     2.575V
388ps     2.647V     2.698V     2.609V
462ps     2.655V     2.699V     2.96V
500ps     2.778V     2.699V     3.065V
567ps     2.992V     2.722V     3.183V
689ps     3.158V     3V         3.292V
921ps     3.258V     3.146V     3.366V
1.418ns   3.296V     3.195V     3.397V
50ns      3.3V       3.2V       3.4V
[Falling Waveform]
R_fixture = 50.000
V_fixture = 3.300
V_fixture_min = 3.200
V_fixture_max = 3.400
|  time   V(typ)   V(min)   V(max)
0s        3.3V       3.2V       3.4V
3.505ns   3.299V     3.197V     3.398V
4.913ns   3.277V     3.178V     3.368V
6.724ns   3.201V     3.117V     3.27V
11.28ns   2.938V     2.904V     2.955V
14.02ns   2.805V     2.802V     2.792V
16.67ns   2.717V     2.741V     2.677V
19.81ns   2.662V     2.709V     2.597V
23.61ns   2.649V     2.702V     2.571V
50ns      2.644V     2.697V     2.566V
[Falling Waveform]
R_fixture = 50.000
V_fixture = 0.000
V_fixture_min = 0.000
V_fixture_max = 0.000
|  time   V(typ)   V(min)   V(max)
0s        699mV      519.6mV    914mV
430ps     698.5mV    519.2mV    905.8mV
455ps     698.7mV    519.2mV    849.1mV
532ps     689.3mV    519.2mV    481mV
575ps     576.3mV    519.5mV    356.6mV
652ps     320.5mV    496.8mV    219.3mV
762ps     160mV      240.3mV    114.1mV
972ps     47.81mV    67.95mV    34.22mV
1.373ns   5.246mV    7.418mV    3.723mV
50ns      87.16uV    -5.445uV   35.24uV
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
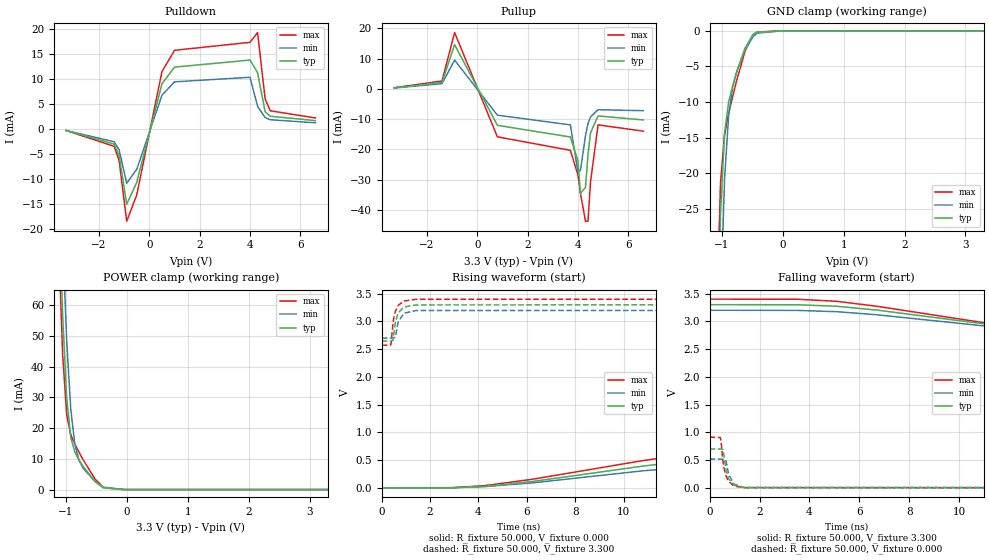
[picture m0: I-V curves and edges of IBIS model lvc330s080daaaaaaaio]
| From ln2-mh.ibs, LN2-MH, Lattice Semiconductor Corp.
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|   Model lvc330s080daaaaaaaio
[Model] lvc330s080daaaaaaaio
Model_type I/O
Polarity   Non-Inverting
Enable   Active-Low
Vinl =  0.800V
Vinh =  2.000V
Vmeas =  1.650V
Cref =  0.0F
Rref =  1.000M
Vref =  0.0V
C_comp   2.000pF   1.500pF   2.500pF
[Temperature Range]   25.000   0.125k   -40.000
[Voltage Range]   3.300V   3.200V   3.400V
[C Comp Corner]
C_comp   2.000pF   1.500pF   2.500pF
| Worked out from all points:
|   slope of the pulldown table from 0 to 0.495 V, typ, clamps not added: 55.7 ohm
|   slope of the pullup table from 0 to 0.495 V, typ, clamps not added: 55.2 ohm
|   GND clamp passes 1 mA (typ) near -0.53 V on its own axis
|   POWER clamp passes 1 mA (typ) near -0.42 V on its own axis
|   rising waveform, R_fixture 50.000, V_fixture 0.000: 20-80 % time 7.6ns typ, 7.24ns min, 8.19ns max; typ from 0 V to 0.699 V
|   rising waveform, R_fixture 50.000, V_fixture 3.300: 20-80 % time 203ps typ, 208ps min, 200ps max; typ from 2.64 V to 3.3 V
|   falling waveform, R_fixture 50.000, V_fixture 3.300: 20-80 % time 7.46ns typ, 7.08ns min, 7.97ns max; typ from 3.3 V to 2.64 V
|   falling waveform, R_fixture 50.000, V_fixture 0.000: 20-80 % time 206ps typ, 210ps min, 203ps max; typ from 0.699 V to 0 V
[Pulldown]
|Voltage   I(typ)   I(min)   I(max)
-3.3V     -346.1uA   -345.8uA   -343.9uA
-1.4V     -3.04mA    -2.573mA   -3.49mA
-1.2V     -5.324mA   -4.185mA   -6.348mA
-900mV    -15.03mA   -10.85mA   -18.43mA
-500mV    -10.66mA   -8.058mA   -13.16mA
500mV     8.96mA     6.694mA    11.38mA
1V        12.3mA     9.366mA    15.66mA
4V        13.71mA    10.28mA    17.24mA
4.3V      11.18mA    4.468mA    19.19mA
4.6V      3.432mA    2.253mA    5.984mA
4.8V      2.519mA    1.816mA    3.602mA
6.6V      1.633mA    1.204mA    2.166mA
[Pullup]
|Voltage   I(typ)   I(min)   I(max)
-3.3V     342.6uA    296.6uA    390.2uA
-1.4V     2.189mA    1.739mA    2.629mA
-900mV    14.63mA    9.513mA    18.62mA
800mV     -12.02mA   -8.67mA    -15.83mA
3.7V      -15.89mA   -11.89mA   -20.29mA
4V        -23.77mA   -27.55mA   -28.43mA
4.1V      -34.58mA   -26.93mA   -34.52mA
4.3V      -32.52mA   -15.47mA   -43.74mA
4.4V      -21.73mA   -11.41mA   -43.66mA
4.5V      -14.48mA   -9.273mA   -30.68mA
4.8V      -8.928mA   -6.87mA    -11.87mA
6.6V      -10.25mA   -7.19mA    -13.97mA
[GND_clamp]
|Voltage   I(typ)   I(min)   I(max)
-3.3V     -1.861A    -1.855A    -1.868A
-1.089V   -50.83mA   -68.22mA   -41.81mA
-1.022V   -25.77mA   -39.11mA   -21.36mA
-955mV    -14.31mA   -20.77mA   -14.6mA
-888mV    -10.03mA   -11.88mA   -11.61mA
-821mV    -7.659mA   -7.903mA   -9.179mA
-754mV    -5.715mA   -5.674mA   -6.892mA
-620mV    -2.446mA   -2.677mA   -2.886mA
-486mV    -500.9uA   -793.7uA   -505.5uA
-419mV    -184.7uA   -329.9uA   -181.9uA
-17mV     -4.77uA    -4.625uA   -5.541uA
3.3V      -213nA     0A         -30.51uA
[POWER_clamp]
|Voltage   I(typ)   I(min)   I(max)
-3.266V   2.002A     2.005A     2.003A
-1.122V   95.85mA    122.4mA    80.77mA
-1.055V   56.44mA    81.14mA    43.86mA
-988mV    29.49mA    48.07mA    24.19mA
-921mV    16.88mA    26.01mA    17.76mA
-854mV    12.16mA    14.63mA    14.72mA
-787mV    9.627mA    9.57mA     12.17mA
-720mV    7.572mA    6.968mA    9.725mA
-519mV    2.543mA    2.542mA    3.339mA
-385mV    550.4uA    786uA      665.7uA
-50mV     13.15uA    11.69uA    15.71uA
3.3V      0A         0A         30.92uA
[Ramp]
| variable   typ   min   max
dV/dt_r   0.429/7.618n   0.319/7.252n   0.561/8.212n
dV/dt_f   0.403/7.484n   0.309/7.089n   0.512/7.987n
R_load = 50.000
[Rising Waveform]
R_fixture = 50.000
V_fixture = 0.000
V_fixture_min = 0.000
V_fixture_max = 0.000
|  time   V(typ)   V(min)   V(max)
0s        87.16uV    -5.445uV   35.24uV
2.919ns   1.825mV    2.733mV    3.037mV
4.268ns   26.77mV    22.84mV    40.38mV
6.263ns   116.4mV    90.85mV    157.1mV
10.8ns    391.8mV    306.9mV    491.2mV
13.45ns   526.3mV    405.5mV    661.3mV
16.23ns   621.5mV    472.1mV    789.7mV
19.47ns   681.3mV    508mV      879.2mV
23.07ns   692.8mV    514mV      907.6mV
50ns      699mV      519.6mV    914mV
[Rising Waveform]
R_fixture = 50.000
V_fixture = 3.300
V_fixture_min = 3.200
V_fixture_max = 3.400
|  time   V(typ)   V(min)   V(max)
0s        2.644V     2.697V     2.566V
372ps     2.647V     2.698V     2.574V
389ps     2.647V     2.698V     2.612V
462ps     2.655V     2.699V     2.959V
498ps     2.769V     2.699V     3.06V
562ps     2.981V     2.714V     3.176V
682ps     3.152V     2.991V     3.288V
917ps     3.257V     3.145V     3.366V
1.417ns   3.296V     3.195V     3.397V
50ns      3.3V       3.2V       3.4V
[Falling Waveform]
R_fixture = 50.000
V_fixture = 3.300
V_fixture_min = 3.200
V_fixture_max = 3.400
|  time   V(typ)   V(min)   V(max)
0s        3.3V       3.2V       3.4V
3.506ns   3.299V     3.197V     3.398V
5.109ns   3.271V     3.173V     3.36V
6.726ns   3.201V     3.117V     3.27V
11.28ns   2.939V     2.904V     2.955V
14.02ns   2.805V     2.803V     2.792V
16.67ns   2.717V     2.741V     2.677V
19.81ns   2.662V     2.709V     2.597V
23.63ns   2.649V     2.702V     2.571V
50ns      2.644V     2.697V     2.566V
[Falling Waveform]
R_fixture = 50.000
V_fixture = 0.000
V_fixture_min = 0.000
V_fixture_max = 0.000
|  time   V(typ)   V(min)   V(max)
0s        699mV      519.6mV    914mV
429ps     698.5mV    519.2mV    906.6mV
454ps     698.7mV    519.2mV    852.5mV
527ps     693.3mV    519.2mV    498.8mV
576ps     573.2mV    519.6mV    354.2mV
659ps     306.1mV    485.8mV    210mV
759ps     163.2mV    245.1mV    116.1mV
973ps     47.61mV    67.54mV    34mV
1.373ns   5.253mV    7.414mV    3.721mV
50ns      87.16uV    -5.445uV   35.24uV
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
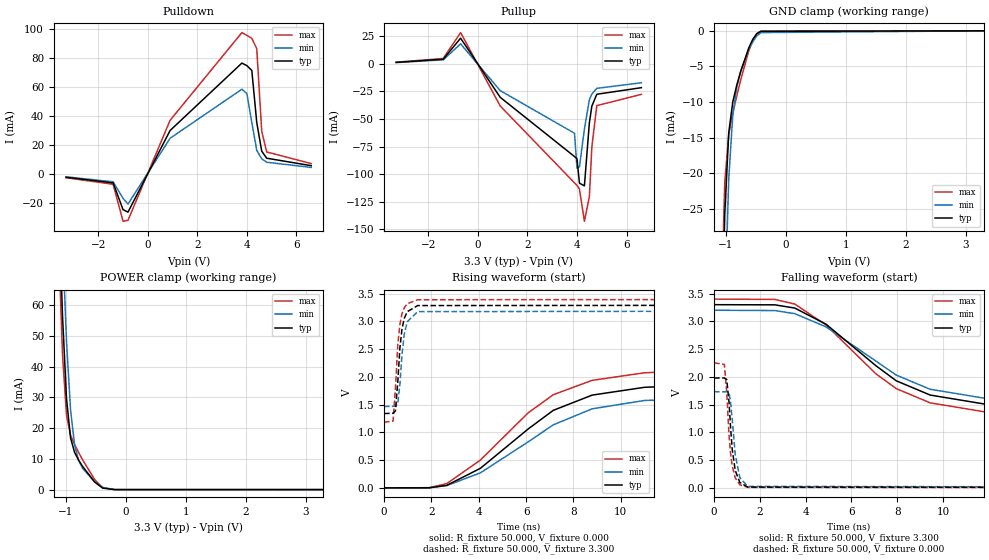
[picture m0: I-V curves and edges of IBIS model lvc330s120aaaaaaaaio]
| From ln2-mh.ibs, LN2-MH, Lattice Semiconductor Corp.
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|   Model lvc330s120aaaaaaaaio
[Model] lvc330s120aaaaaaaaio
Model_type I/O
Polarity   Non-Inverting
Enable   Active-Low
Vinl =  0.800V
Vinh =  2.000V
Vmeas =  1.650V
Cref =  0.0F
Rref =  1.000M
Vref =  0.0V
C_comp   2.000pF   1.500pF   2.500pF
[Temperature Range]   25.000   0.125k   -40.000
[Voltage Range]   3.300V   3.200V   3.400V
[C Comp Corner]
C_comp   2.000pF   1.500pF   2.500pF
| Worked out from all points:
|   slope of the pulldown table from 0 to 0.495 V, typ, clamps not added: 26.6 ohm
|   slope of the pullup table from 0 to 0.495 V, typ, clamps not added: 26.5 ohm
|   GND clamp passes 1 mA (typ) near -0.54 V on its own axis
|   POWER clamp passes 1 mA (typ) near -0.43 V on its own axis
|   rising waveform, R_fixture 50.000, V_fixture 0.000: 20-80 % time 3.87ns typ, 4.06ns min, 3.81ns max; typ from 0 V to 1.98 V
|   rising waveform, R_fixture 50.000, V_fixture 3.300: 20-80 % time 220ps typ, 231ps min, 211ps max; typ from 1.34 V to 3.3 V
|   falling waveform, R_fixture 50.000, V_fixture 3.300: 20-80 % time 3.96ns typ, 4.05ns min, 3.94ns max; typ from 3.3 V to 1.34 V
|   falling waveform, R_fixture 50.000, V_fixture 0.000: 20-80 % time 240ps typ, 253ps min, 232ps max; typ from 1.98 V to 0 V
[Pulldown]
|Voltage   I(typ)   I(min)   I(max)
-3.3V     -2.345mA   -2.076mA   -2.727mA
-1.4V     -6.266mA   -5.489mA   -7.185mA
-1V       -24.72mA   -16.92mA   -32.74mA
-800mV    -26.41mA   -20.84mA   -32.04mA
900mV     29.87mA    24.53mA    36.9mA
3.8V      76.38mA    58.35mA    97.42mA
4V        74.61mA    55.38mA    95.49mA
4.2V      71.32mA    35.39mA    93.42mA
4.4V      35.34mA    16.18mA    86.33mA
4.6V      15.67mA    10.33mA    29.42mA
4.8V      10.77mA    7.994mA    15.09mA
6.6V      5.609mA    4.391mA    7.052mA
[Pullup]
|Voltage   I(typ)   I(min)   I(max)
-3.3V     1.285mA    1.145mA    1.475mA
-1.4V     4.192mA    3.596mA    4.847mA
-700mV    23.22mA    18.08mA    28.31mA
900mV     -30.32mA   -24.27mA   -38.17mA
3.9V      -83.95mA   -62.85mA   -107.8mA
4V        -85.99mA   -94.42mA   -110.1mA
4.1V      -108.1mA   -93.25mA   -113.4mA
4.3V      -110.5mA   -58.98mA   -142.6mA
4.5V      -53.47mA   -32.44mA   -120.4mA
4.6V      -38.36mA   -27.32mA   -75.28mA
4.8V      -27.56mA   -22.19mA   -37.84mA
6.6V      -21.6mA    -17.14mA   -27.67mA
[GND_clamp]
|Voltage   I(typ)   I(min)   I(max)
-3.3V     -1.861A    -1.855A    -1.868A
-1.089V   -50.81mA   -68.2mA    -41.77mA
-1.022V   -25.74mA   -39.08mA   -21.31mA
-955mV    -14.26mA   -20.73mA   -14.54mA
-888mV    -9.982mA   -11.84mA   -11.55mA
-821mV    -7.603mA   -7.856mA   -9.113mA
-754mV    -5.655mA   -5.623mA   -6.821mA
-620mV    -2.371mA   -2.616mA   -2.797mA
-553mV    -1.172mA   -1.518mA   -1.313mA
-486mV    -396.2uA   -716.4uA   -376.4uA
-419mV    -71.95uA   -244.9uA   -42.84uA
3.3V      0A         0A         0A
[POWER_clamp]
|Voltage   I(typ)   I(min)   I(max)
-3.266V   2.002A     2.005A     2.003A
-1.122V   95.84mA    122.3mA    80.75mA
-1.055V   56.42mA    81.13mA    43.84mA
-988mV    29.46mA    48.05mA    24.15mA
-921mV    16.84mA    25.99mA    17.71mA
-854mV    12.12mA    14.6mA     14.67mA
-787mV    9.585mA    9.535mA    12.12mA
-720mV    7.529mA    6.931mA    9.676mA
-519mV    2.487mA    2.496mA    3.276mA
-385mV    477.3uA    731.6uA    579.8uA
-184mV    1.009uA    11.15uA    276.7nA
3.3V      0A         0A         0A
[Ramp]
| variable   typ   min   max
dV/dt_r   1.215/3.876n   1.062/4.069n   1.382/3.816n
dV/dt_f   1.204/3.959n   1.065/4.062n   1.361/3.957n
R_load = 50.000
[Rising Waveform]
R_fixture = 50.000
V_fixture = 0.000
V_fixture_min = 0.000
V_fixture_max = 0.000
|  time   V(typ)   V(min)   V(max)
0s        1.645uV    6.732uV    585.8nV
1.911ns   1.114mV    2.203mV    2.842mV
2.657ns   45.69mV    41.8mV     77.58mV
4.07ns    351.8mV    270.2mV    500.1mV
6.089ns   1.061V     828.6mV    1.352V
7.146ns   1.396V     1.135V     1.678V
8.789ns   1.671V     1.424V     1.937V
10.99ns   1.811V     1.574V     2.072V
19.02ns   1.963V     1.711V     2.239V
50ns      1.979V     1.73V      2.254V
[Rising Waveform]
R_fixture = 50.000
V_fixture = 3.300
V_fixture_min = 3.200
V_fixture_max = 3.400
|  time   V(typ)   V(min)   V(max)
0s        1.339V     1.466V     1.181V
386ps     1.344V     1.469V     1.203V
486ps     1.389V     1.472V     1.801V
585ps     1.915V     1.519V     2.581V
674ps     2.525V     1.872V     2.948V
760ps     2.858V     2.395V     3.133V
858ps     3.053V     2.77V      3.245V
984ps     3.174V     2.991V     3.318V
1.423ns   3.284V     3.175V     3.389V
50ns      3.3V       3.2V       3.4V
[Falling Waveform]
R_fixture = 50.000
V_fixture = 3.300
V_fixture_min = 3.200
V_fixture_max = 3.400
|  time   V(typ)   V(min)   V(max)
0s        3.3V       3.2V       3.4V
2.655ns   3.297V     3.194V     3.395V
3.525ns   3.239V     3.138V     3.311V
4.894ns   2.947V     2.899V     2.932V
7.068ns   2.2V       2.283V     2.054V
7.955ns   1.929V     2.032V     1.788V
9.435ns   1.672V     1.776V     1.532V
11.78ns   1.512V     1.617V     1.372V
20.08ns   1.353V     1.483V     1.194V
50ns      1.339V     1.466V     1.181V
[Falling Waveform]
R_fixture = 50.000
V_fixture = 0.000
V_fixture_min = 0.000
V_fixture_max = 0.000
|  time   V(typ)   V(min)   V(max)
0s        1.979V     1.73V      2.254V
451ps     1.98V      1.731V     2.223V
553ps     1.951V     1.731V     1.715V
652ps     1.547V     1.717V     951.2mV
716ps     1.117V     1.556V     637.1mV
792ps     696.4mV    1.244V     399.5mV
924ps     314.2mV    595.5mV    179.9mV
1.125ns   97.22mV    183.6mV    56.23mV
1.472ns   14.27mV    26.35mV    8.554mV
50ns      1.645uV    6.732uV    579.9nV
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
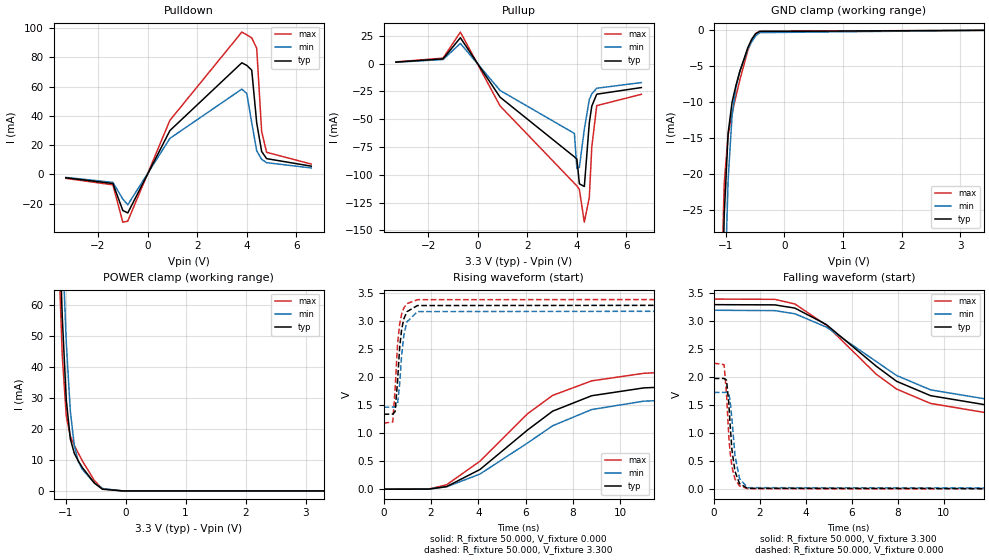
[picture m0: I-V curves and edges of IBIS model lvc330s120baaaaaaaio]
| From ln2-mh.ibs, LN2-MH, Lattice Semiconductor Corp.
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|   Model lvc330s120baaaaaaaio
[Model] lvc330s120baaaaaaaio
Model_type I/O
Polarity   Non-Inverting
Enable   Active-Low
Vinl =  0.800V
Vinh =  2.000V
Vmeas =  1.650V
Cref =  0.0F
Rref =  1.000M
Vref =  0.0V
C_comp   2.000pF   1.500pF   2.500pF
[Temperature Range]   25.000   0.125k   -40.000
[Voltage Range]   3.300V   3.200V   3.400V
[C Comp Corner]
C_comp   2.000pF   1.500pF   2.500pF
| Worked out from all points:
|   slope of the pulldown table from 0 to 0.495 V, typ, clamps not added: 26.6 ohm
|   slope of the pullup table from 0 to 0.495 V, typ, clamps not added: 26.6 ohm
|   GND clamp passes 1 mA (typ) near -0.53 V on its own axis
|   POWER clamp passes 1 mA (typ) near -0.42 V on its own axis
|   rising waveform, R_fixture 50.000, V_fixture 0.000: 20-80 % time 3.87ns typ, 4.06ns min, 3.81ns max; typ from 0 V to 1.98 V
|   rising waveform, R_fixture 50.000, V_fixture 3.300: 20-80 % time 220ps typ, 231ps min, 211ps max; typ from 1.34 V to 3.3 V
|   falling waveform, R_fixture 50.000, V_fixture 3.300: 20-80 % time 3.96ns typ, 4.05ns min, 3.94ns max; typ from 3.3 V to 1.34 V
|   falling waveform, R_fixture 50.000, V_fixture 0.000: 20-80 % time 240ps typ, 253ps min, 232ps max; typ from 1.98 V to 0 V
[Pulldown]
|Voltage   I(typ)   I(min)   I(max)
-3.3V     -2.343mA   -2.074mA   -2.726mA
-1.4V     -6.263mA   -5.486mA   -7.183mA
-1V       -24.71mA   -16.91mA   -32.72mA
-800mV    -26.39mA   -20.82mA   -32.02mA
900mV     29.96mA    24.63mA    36.99mA
3.8V      76.32mA    58.31mA    97.33mA
4V        74.56mA    55.34mA    95.44mA
4.2V      71.28mA    35.37mA    93.37mA
4.4V      35.32mA    16.17mA    86.3mA
4.6V      15.66mA    10.32mA    29.41mA
4.8V      10.76mA    7.989mA    15.09mA
6.6V      5.607mA    4.389mA    7.049mA
[Pullup]
|Voltage   I(typ)   I(min)   I(max)
-3.3V     1.282mA    1.143mA    1.472mA
-1.4V     4.186mA    3.59mA     4.84mA
-700mV    23.18mA    18.05mA    28.26mA
900mV     -30.23mA   -24.18mA   -38.08mA
3.9V      -83.91mA   -62.82mA   -107.7mA
4V        -85.97mA   -94.4mA    -110mA
4.1V      -108.1mA   -93.24mA   -113.3mA
4.3V      -110.5mA   -58.98mA   -142.6mA
4.5V      -53.46mA   -32.44mA   -120.4mA
4.6V      -38.35mA   -27.31mA   -75.28mA
4.8V      -27.55mA   -22.19mA   -37.84mA
6.6V      -21.6mA    -17.13mA   -27.66mA
[GND_clamp]
|Voltage   I(typ)   I(min)   I(max)
-3.3V     -1.861A    -1.855A    -1.868A
-1.089V   -50.81mA   -68.21mA   -41.78mA
-1.022V   -25.75mA   -39.09mA   -21.32mA
-955mV    -14.27mA   -20.74mA   -14.55mA
-888mV    -9.999mA   -11.85mA   -11.57mA
-821mV    -7.623mA   -7.877mA   -9.132mA
-754mV    -5.679mA   -5.648mA   -6.844mA
-620mV    -2.407mA   -2.651mA   -2.831mA
-553mV    -1.221mA   -1.563mA   -1.361mA
-486mV    -463.6uA   -775.1uA   -445.5uA
-419mV    -157.8uA   -320.2uA   -132.1uA
3.4V      0A         0A         0A
[POWER_clamp]
|Voltage   I(typ)   I(min)   I(max)
-3.266V   2.002A     2.005A     2.003A
-1.122V   95.85mA    122.4mA    80.77mA
-1.055V   56.44mA    81.14mA    43.86mA
-988mV    29.49mA    48.07mA    24.19mA
-921mV    16.88mA    26.01mA    17.76mA
-854mV    12.16mA    14.63mA    14.72mA
-787mV    9.627mA    9.57mA     12.17mA
-720mV    7.572mA    6.968mA    9.725mA
-519mV    2.543mA    2.542mA    3.339mA
-385mV    550.4uA    786uA      665.7uA
-50mV     13.15uA    11.69uA    15.71uA
3.3V      0A         0A         0A
[Ramp]
| variable   typ   min   max
dV/dt_r   1.215/3.867n   1.062/4.072n   1.382/3.805n
dV/dt_f   1.204/3.960n   1.065/4.060n   1.361/3.946n
R_load = 50.000
[Rising Waveform]
R_fixture = 50.000
V_fixture = 0.000
V_fixture_min = 0.000
V_fixture_max = 0.000
|  time   V(typ)   V(min)   V(max)
0s        1.645uV    6.731uV    586.4nV
1.911ns   1.115mV    2.204mV    2.85mV
2.659ns   45.92mV    41.98mV    78mV
4.07ns    351.8mV    270.2mV    500.2mV
6.083ns   1.059V     826.7mV    1.35V
7.141ns   1.395V     1.134V     1.677V
8.789ns   1.671V     1.424V     1.937V
10.99ns   1.811V     1.574V     2.072V
19.02ns   1.963V     1.711V     2.239V
50ns      1.979V     1.73V      2.254V
[Rising Waveform]
R_fixture = 50.000
V_fixture = 3.300
V_fixture_min = 3.200
V_fixture_max = 3.400
|  time   V(typ)   V(min)   V(max)
0s        1.339V     1.466V     1.181V
386ps     1.344V     1.469V     1.202V
486ps     1.389V     1.472V     1.799V
587ps     1.931V     1.524V     2.592V
676ps     2.536V     1.883V     2.953V
760ps     2.858V     2.395V     3.132V
856ps     3.05V      2.765V     3.243V
984ps     3.174V     2.991V     3.318V
1.426ns   3.284V     3.176V     3.389V
50ns      3.3V       3.2V       3.4V
[Falling Waveform]
R_fixture = 50.000
V_fixture = 3.300
V_fixture_min = 3.200
V_fixture_max = 3.400
|  time   V(typ)   V(min)   V(max)
0s        3.3V       3.2V       3.4V
2.658ns   3.296V     3.193V     3.395V
3.529ns   3.238V     3.137V     3.312V
4.892ns   2.946V     2.9V       2.934V
7.071ns   2.198V     2.282V     2.055V
7.953ns   1.929V     2.033V     1.79V
9.432ns   1.672V     1.776V     1.533V
11.76ns   1.513V     1.618V     1.373V
20.1ns    1.353V     1.483V     1.194V
50ns      1.339V     1.466V     1.181V
[Falling Waveform]
R_fixture = 50.000
V_fixture = 0.000
V_fixture_min = 0.000
V_fixture_max = 0.000
|  time   V(typ)   V(min)   V(max)
0s        1.979V     1.73V      2.254V
449ps     1.98V      1.731V     2.227V
553ps     1.951V     1.731V     1.712V
653ps     1.543V     1.715V     942.9mV
713ps     1.138V     1.566V     647.4mV
792ps     697.2mV    1.244V     398.5mV
923ps     316.4mV    599mV      180.6mV
1.12ns    100.1mV    189mV      57.71mV
1.468ns   14.59mV    26.93mV    8.714mV
50ns      1.645uV    6.731uV    580.4nV
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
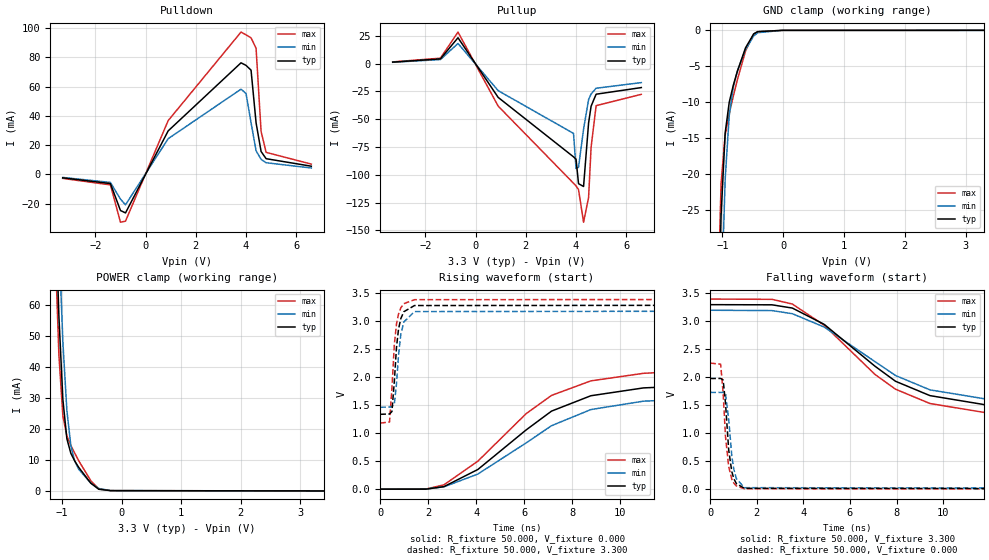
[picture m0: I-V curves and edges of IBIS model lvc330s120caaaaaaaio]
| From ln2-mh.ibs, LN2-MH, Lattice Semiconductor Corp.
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|   Model lvc330s120caaaaaaaio
[Model] lvc330s120caaaaaaaio
Model_type I/O
Polarity   Non-Inverting
Enable   Active-Low
Vinl =  0.800V
Vinh =  2.000V
Vmeas =  1.650V
Cref =  0.0F
Rref =  1.000M
Vref =  0.0V
C_comp   2.000pF   1.500pF   2.500pF
[Temperature Range]   25.000   0.125k   -40.000
[Voltage Range]   3.300V   3.200V   3.400V
[C Comp Corner]
C_comp   2.000pF   1.500pF   2.500pF
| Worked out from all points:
|   slope of the pulldown table from 0 to 0.495 V, typ, clamps not added: 26.7 ohm
|   slope of the pullup table from 0 to 0.495 V, typ, clamps not added: 26.5 ohm
|   GND clamp passes 1 mA (typ) near -0.53 V on its own axis
|   POWER clamp passes 1 mA (typ) near -0.42 V on its own axis
|   rising waveform, R_fixture 50.000, V_fixture 0.000: 20-80 % time 3.87ns typ, 4.06ns min, 3.81ns max; typ from 0 V to 1.98 V
|   rising waveform, R_fixture 50.000, V_fixture 3.300: 20-80 % time 220ps typ, 231ps min, 211ps max; typ from 1.34 V to 3.3 V
|   falling waveform, R_fixture 50.000, V_fixture 3.300: 20-80 % time 3.96ns typ, 4.05ns min, 3.94ns max; typ from 3.3 V to 1.34 V
|   falling waveform, R_fixture 50.000, V_fixture 0.000: 20-80 % time 240ps typ, 253ps min, 232ps max; typ from 1.98 V to 0 V
[Pulldown]
|Voltage   I(typ)   I(min)   I(max)
-3.3V     -2.338mA   -2.07mA    -2.72mA
-1.4V     -6.255mA   -5.479mA   -7.174mA
-1V       -24.68mA   -16.89mA   -32.68mA
-800mV    -26.35mA   -20.79mA   -31.98mA
900mV     29.78mA    24.44mA    36.81mA
3.8V      76.34mA    58.32mA    97.36mA
4V        74.59mA    55.36mA    95.47mA
4.2V      71.31mA    35.38mA    93.41mA
4.4V      35.33mA    16.18mA    86.32mA
4.6V      15.67mA    10.33mA    29.41mA
4.8V      10.76mA    7.992mA    15.09mA
6.6V      5.609mA    4.391mA    7.052mA
[Pullup]
|Voltage   I(typ)   I(min)   I(max)
-3.3V     1.285mA    1.144mA    1.475mA
-1.4V     4.19mA     3.594mA    4.845mA
-700mV    23.2mA     18.06mA    28.29mA
900mV     -30.42mA   -24.37mA   -38.26mA
3.9V      -83.87mA   -62.79mA   -107.6mA
4V        -85.93mA   -94.37mA   -110mA
4.1V      -108mA     -93.21mA   -113.3mA
4.3V      -110.5mA   -58.96mA   -142.6mA
4.5V      -53.45mA   -32.43mA   -120.4mA
4.6V      -38.34mA   -27.31mA   -75.26mA
4.8V      -27.55mA   -22.18mA   -37.83mA
6.6V      -21.59mA   -17.13mA   -27.66mA
[GND_clamp]
|Voltage   I(typ)   I(min)   I(max)
-3.3V     -1.861A    -1.855A    -1.868A
-1.089V   -50.83mA   -68.22mA   -41.81mA
-1.022V   -25.77mA   -39.11mA   -21.36mA
-955mV    -14.31mA   -20.77mA   -14.6mA
-888mV    -10.03mA   -11.88mA   -11.61mA
-821mV    -7.659mA   -7.903mA   -9.179mA
-754mV    -5.715mA   -5.674mA   -6.892mA
-620mV    -2.446mA   -2.677mA   -2.886mA
-486mV    -500.9uA   -793.7uA   -505.5uA
-419mV    -184.7uA   -329.9uA   -181.9uA
-17mV     -4.77uA    -4.625uA   -5.541uA
3.3V      0A         0A         0A
[POWER_clamp]
|Voltage   I(typ)   I(min)   I(max)
-3.266V   2.002A     2.005A     2.003A
-1.122V   95.84mA    122.3mA    80.75mA
-1.055V   56.43mA    81.13mA    43.84mA
-988mV    29.47mA    48.06mA    24.16mA
-921mV    16.85mA    26mA       17.72mA
-854mV    12.14mA    14.62mA    14.69mA
-787mV    9.602mA    9.553mA    12.13mA
-720mV    7.548mA    6.952mA    9.693mA
-519mV    2.524mA    2.533mA    3.308mA
-385mV    541.5uA    790.3uA    641.3uA
-184mV    92.6uA     101.7uA    92.48uA
3.4V      0A         0A         0A
[Ramp]
| variable   typ   min   max
dV/dt_r   1.215/3.888n   1.062/4.069n   1.382/3.805n
dV/dt_f   1.204/3.969n   1.065/4.056n   1.361/3.953n
R_load = 50.000
[Rising Waveform]
R_fixture = 50.000
V_fixture = 0.000
V_fixture_min = 0.000
V_fixture_max = 0.000
|  time   V(typ)   V(min)   V(max)
0s        58.57uV    -8.068uV   23.24uV
1.915ns   1.2mV      2.254mV    2.975mV
2.657ns   45.75mV    41.78mV    77.66mV
4.07ns    351.8mV    270.2mV    500.2mV
6.083ns   1.059V     826.7mV    1.35V
7.144ns   1.396V     1.135V     1.677V
8.785ns   1.671V     1.424V     1.937V
10.98ns   1.811V     1.574V     2.072V
19.02ns   1.963V     1.711V     2.239V
50ns      1.979V     1.73V      2.254V
[Rising Waveform]
R_fixture = 50.000
V_fixture = 3.300
V_fixture_min = 3.200
V_fixture_max = 3.400
|  time   V(typ)   V(min)   V(max)
0s        1.339V     1.466V     1.181V
386ps     1.344V     1.469V     1.202V
486ps     1.389V     1.472V     1.799V
587ps     1.931V     1.524V     2.592V
676ps     2.536V     1.883V     2.953V
760ps     2.858V     2.395V     3.132V
856ps     3.05V      2.765V     3.243V
984ps     3.174V     2.991V     3.318V
1.426ns   3.284V     3.176V     3.389V
50ns      3.3V       3.2V       3.4V
[Falling Waveform]
R_fixture = 50.000
V_fixture = 3.300
V_fixture_min = 3.200
V_fixture_max = 3.400
|  time   V(typ)   V(min)   V(max)
0s        3.3V       3.2V       3.4V
2.654ns   3.297V     3.194V     3.395V
3.525ns   3.239V     3.138V     3.311V
4.891ns   2.948V     2.9V       2.932V
7.07ns    2.2V       2.282V     2.053V
7.954ns   1.93V      2.033V     1.788V
9.434ns   1.673V     1.776V     1.532V
11.77ns   1.512V     1.617V     1.372V
20.11ns   1.353V     1.483V     1.194V
50ns      1.339V     1.466V     1.181V
[Falling Waveform]
R_fixture = 50.000
V_fixture = 0.000
V_fixture_min = 0.000
V_fixture_max = 0.000
|  time   V(typ)   V(min)   V(max)
0s        1.979V     1.73V      2.254V
445ps     1.98V      1.731V     2.235V
552ps     1.953V     1.731V     1.722V
653ps     1.542V     1.715V     943.9mV
791ps     701mV      1.248V     401.6mV
924ps     314.4mV    594.5mV    179.8mV
1.013ns   185.6mV    351.7mV    106.8mV
1.124ns   97.86mV    184.4mV    56.51mV
1.468ns   14.64mV    26.89mV    8.746mV
50ns      58.57uV    -8.068uV   23.24uV
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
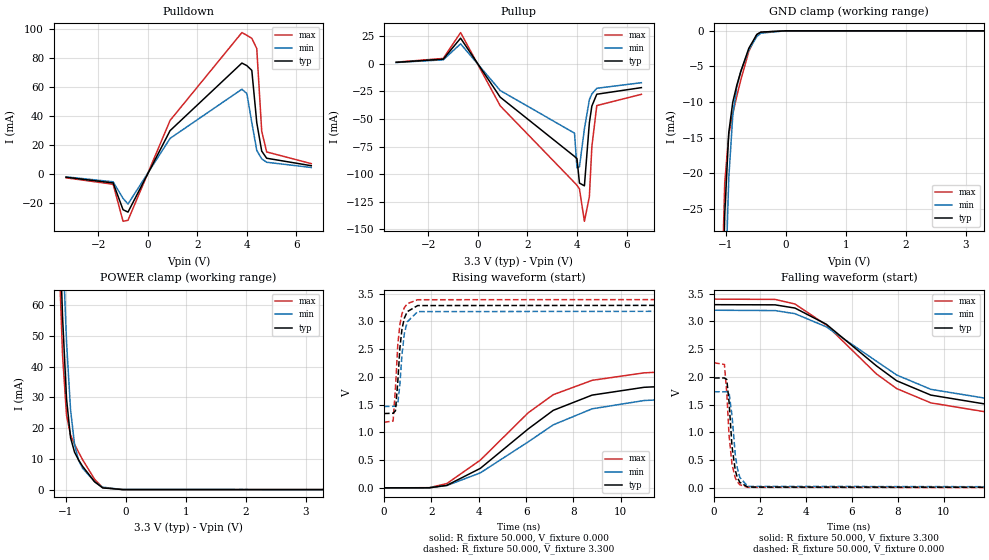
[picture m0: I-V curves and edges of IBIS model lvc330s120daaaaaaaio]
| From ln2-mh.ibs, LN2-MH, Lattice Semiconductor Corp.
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|   Model lvc330s120daaaaaaaio
[Model] lvc330s120daaaaaaaio
Model_type I/O
Polarity   Non-Inverting
Enable   Active-Low
Vinl =  0.800V
Vinh =  2.000V
Vmeas =  1.650V
Cref =  0.0F
Rref =  1.000M
Vref =  0.0V
C_comp   2.000pF   1.500pF   2.500pF
[Temperature Range]   25.000   0.125k   -40.000
[Voltage Range]   3.300V   3.200V   3.400V
[C Comp Corner]
C_comp   2.000pF   1.500pF   2.500pF
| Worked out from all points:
|   slope of the pulldown table from 0 to 0.495 V, typ, clamps not added: 26.7 ohm
|   slope of the pullup table from 0 to 0.495 V, typ, clamps not added: 26.6 ohm
|   GND clamp passes 1 mA (typ) near -0.53 V on its own axis
|   POWER clamp passes 1 mA (typ) near -0.42 V on its own axis
|   rising waveform, R_fixture 50.000, V_fixture 0.000: 20-80 % time 3.87ns typ, 4.06ns min, 3.81ns max; typ from 0 V to 1.98 V
|   rising waveform, R_fixture 50.000, V_fixture 3.300: 20-80 % time 220ps typ, 231ps min, 211ps max; typ from 1.34 V to 3.3 V
|   falling waveform, R_fixture 50.000, V_fixture 3.300: 20-80 % time 3.96ns typ, 4.05ns min, 3.94ns max; typ from 3.3 V to 1.34 V
|   falling waveform, R_fixture 50.000, V_fixture 0.000: 20-80 % time 240ps typ, 253ps min, 232ps max; typ from 1.98 V to 0 V
[Pulldown]
|Voltage   I(typ)   I(min)   I(max)
-3.3V     -2.338mA   -2.07mA    -2.72mA
-1.4V     -6.255mA   -5.479mA   -7.174mA
-1V       -24.68mA   -16.89mA   -32.68mA
-800mV    -26.35mA   -20.79mA   -31.98mA
900mV     29.78mA    24.44mA    36.81mA
3.8V      76.32mA    58.31mA    97.33mA
4V        74.56mA    55.34mA    95.44mA
4.2V      71.28mA    35.37mA    93.37mA
4.4V      35.32mA    16.17mA    86.3mA
4.6V      15.66mA    10.32mA    29.41mA
4.8V      10.76mA    7.989mA    15.09mA
6.6V      5.607mA    4.389mA    7.049mA
[Pullup]
|Voltage   I(typ)   I(min)   I(max)
-3.3V     1.282mA    1.143mA    1.472mA
-1.4V     4.186mA    3.59mA     4.84mA
-700mV    23.18mA    18.05mA    28.26mA
900mV     -30.23mA   -24.18mA   -38.08mA
3.9V      -83.87mA   -62.79mA   -107.6mA
4V        -85.93mA   -94.37mA   -110mA
4.1V      -108mA     -93.21mA   -113.3mA
4.3V      -110.5mA   -58.96mA   -142.6mA
4.5V      -53.45mA   -32.43mA   -120.4mA
4.6V      -38.34mA   -27.31mA   -75.26mA
4.8V      -27.55mA   -22.18mA   -37.83mA
6.6V      -21.59mA   -17.13mA   -27.65mA
[GND_clamp]
|Voltage   I(typ)   I(min)   I(max)
-3.3V     -1.861A    -1.855A    -1.868A
-1.089V   -50.83mA   -68.22mA   -41.81mA
-1.022V   -25.77mA   -39.11mA   -21.36mA
-955mV    -14.31mA   -20.77mA   -14.6mA
-888mV    -10.03mA   -11.88mA   -11.61mA
-821mV    -7.659mA   -7.903mA   -9.179mA
-754mV    -5.715mA   -5.674mA   -6.892mA
-620mV    -2.446mA   -2.677mA   -2.886mA
-486mV    -500.9uA   -793.7uA   -505.5uA
-419mV    -184.7uA   -329.9uA   -181.9uA
-17mV     -4.77uA    -4.625uA   -5.541uA
3.3V      -213nA     0A         -30.51uA
[POWER_clamp]
|Voltage   I(typ)   I(min)   I(max)
-3.266V   2.002A     2.005A     2.003A
-1.122V   95.85mA    122.4mA    80.77mA
-1.055V   56.44mA    81.14mA    43.86mA
-988mV    29.49mA    48.07mA    24.19mA
-921mV    16.88mA    26.01mA    17.76mA
-854mV    12.16mA    14.63mA    14.72mA
-787mV    9.627mA    9.57mA     12.17mA
-720mV    7.572mA    6.968mA    9.725mA
-519mV    2.543mA    2.542mA    3.339mA
-385mV    550.4uA    786uA      665.7uA
-50mV     13.15uA    11.69uA    15.71uA
3.3V      0A         0A         30.92uA
[Ramp]
| variable   typ   min   max
dV/dt_r   1.215/3.884n   1.062/4.069n   1.382/3.805n
dV/dt_f   1.204/3.969n   1.065/4.062n   1.361/3.947n
R_load = 50.000
[Rising Waveform]
R_fixture = 50.000
V_fixture = 0.000
V_fixture_min = 0.000
V_fixture_max = 0.000
|  time   V(typ)   V(min)   V(max)
0s        58.57uV    -8.068uV   23.24uV
1.915ns   1.2mV      2.254mV    2.975mV
2.657ns   45.75mV    41.78mV    77.65mV
4.068ns   351.2mV    269.8mV    499.4mV
6.088ns   1.061V     828.3mV    1.352V
7.145ns   1.396V     1.135V     1.678V
8.786ns   1.671V     1.424V     1.937V
10.99ns   1.812V     1.574V     2.072V
18.82ns   1.962V     1.71V      2.238V
50ns      1.979V     1.73V      2.254V
[Rising Waveform]
R_fixture = 50.000
V_fixture = 3.300
V_fixture_min = 3.200
V_fixture_max = 3.400
|  time   V(typ)   V(min)   V(max)
0s        1.339V     1.466V     1.181V
387ps     1.344V     1.469V     1.204V
486ps     1.389V     1.472V     1.8V
585ps     1.915V     1.519V     2.58V
674ps     2.525V     1.872V     2.948V
760ps     2.858V     2.395V     3.133V
861ps     3.057V     2.778V     3.247V
984ps     3.174V     2.991V     3.318V
1.423ns   3.284V     3.175V     3.389V
50ns      3.3V       3.2V       3.4V
[Falling Waveform]
R_fixture = 50.000
V_fixture = 3.300
V_fixture_min = 3.200
V_fixture_max = 3.400
|  time   V(typ)   V(min)   V(max)
0s        3.3V       3.2V       3.4V
2.654ns   3.297V     3.194V     3.395V
3.522ns   3.239V     3.138V     3.312V
4.89ns    2.947V     2.9V       2.933V
7.07ns    2.198V     2.282V     2.053V
7.954ns   1.929V     2.033V     1.788V
9.44ns    1.671V     1.775V     1.531V
11.78ns   1.512V     1.617V     1.372V
20.1ns    1.353V     1.483V     1.194V
50ns      1.339V     1.466V     1.181V
[Falling Waveform]
R_fixture = 50.000
V_fixture = 0.000
V_fixture_min = 0.000
V_fixture_max = 0.000
|  time   V(typ)   V(min)   V(max)
0s        1.979V     1.73V      2.254V
451ps     1.98V      1.731V     2.223V
553ps     1.952V     1.731V     1.714V
652ps     1.549V     1.717V     950.6mV
781ps     747.7mV    1.301V     427.3mV
922ps     318.6mV    602.5mV    182mV
1.011ns   188.1mV    356.3mV    108.1mV
1.123ns   98.54mV    185.7mV    56.85mV
1.468ns   14.65mV    26.92mV    8.748mV
50ns      58.57uV    -8.068uV   23.24uV
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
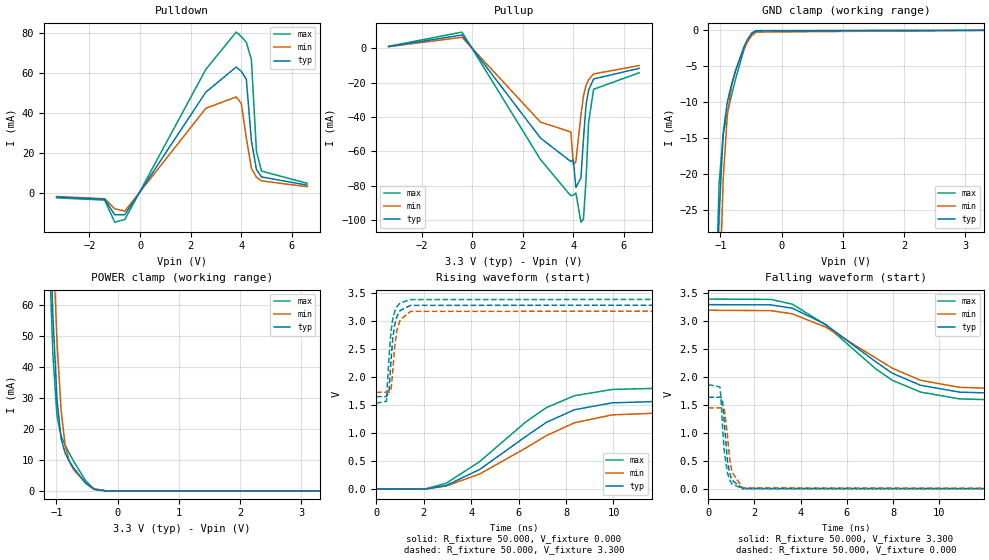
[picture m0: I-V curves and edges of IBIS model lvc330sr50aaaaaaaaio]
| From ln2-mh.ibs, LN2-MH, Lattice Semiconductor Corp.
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|   Model lvc330sr50aaaaaaaaio
[Model] lvc330sr50aaaaaaaaio
Model_type I/O
Polarity   Non-Inverting
Enable   Active-Low
Vinl =  0.800V
Vinh =  2.000V
Vmeas =  1.650V
Cref =  0.0F
Rref =  1.000M
Vref =  0.0V
C_comp   2.000pF   1.500pF   2.500pF
[Temperature Range]   25.000   0.125k   -40.000
[Voltage Range]   3.300V   3.200V   3.400V
[C Comp Corner]
C_comp   2.000pF   1.500pF   2.500pF
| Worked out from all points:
|   slope of the pulldown table from 0 to 0.495 V, typ, clamps not added: 49.7 ohm
|   slope of the pullup table from 0 to 0.495 V, typ, clamps not added: 49.7 ohm
|   GND clamp passes 1 mA (typ) near -0.54 V on its own axis
|   POWER clamp passes 1 mA (typ) near -0.43 V on its own axis
|   rising waveform, R_fixture 50.000, V_fixture 0.000: 20-80 % time 3.43ns typ, 3.74ns min, 3.34ns max; typ from 0 V to 1.64 V
|   rising waveform, R_fixture 50.000, V_fixture 3.300: 20-80 % time 216ps typ, 226ps min, 208ps max; typ from 1.66 V to 3.3 V
|   falling waveform, R_fixture 50.000, V_fixture 3.300: 20-80 % time 3.39ns typ, 3.6ns min, 3.34ns max; typ from 3.3 V to 1.66 V
|   falling waveform, R_fixture 50.000, V_fixture 0.000: 20-80 % time 230ps typ, 242ps min, 222ps max; typ from 1.64 V to 0 V
[Pulldown]
|Voltage   I(typ)   I(min)   I(max)
-3.3V     -1.987mA   -1.721mA   -2.37mA
-1.4V     -3.103mA   -2.837mA   -3.517mA
-1V       -10.87mA   -7.842mA   -14.55mA
-600mV    -10.79mA   -8.969mA   -13.15mA
2.6V      50.46mA    42.38mA    61.83mA
3.8V      63.01mA    48.05mA    80.47mA
4V        60.9mA     44.88mA    78.25mA
4.2V      56.9mA     27.47mA    75.35mA
4.4V      26.2mA     12.44mA    66.73mA
4.6V      11.72mA    7.921mA    20.84mA
4.8V      8.067mA    6.103mA    10.99mA
6.6V      3.982mA    3.187mA    4.9mA
[Pullup]
|Voltage   I(typ)   I(min)   I(max)
-3.3V     936.9uA    844uA      1.078mA
-400mV    7.638mA    6.288mA    9.328mA
2.7V      -52.19mA   -42.95mA   -64.68mA
3.9V      -65.87mA   -48.65mA   -85.78mA
4V        -64.94mA   -67.79mA   -85.26mA
4.1V      -80.91mA   -65.79mA   -84.16mA
4.3V      -75.33mA   -38.93mA   -101.1mA
4.4V      -52.83mA   -27.68mA   -99.22mA
4.5V      -33.23mA   -21.78mA   -76.82mA
4.6V      -24.51mA   -18.44mA   -43.56mA
4.8V      -17.92mA   -14.99mA   -23.89mA
6.6V      -11.71mA   -10.11mA   -14.32mA
[GND_clamp]
|Voltage   I(typ)   I(min)   I(max)
-3.3V     -1.861A    -1.855A    -1.868A
-1.089V   -50.81mA   -68.2mA    -41.77mA
-1.022V   -25.74mA   -39.08mA   -21.31mA
-955mV    -14.26mA   -20.73mA   -14.54mA
-888mV    -9.982mA   -11.84mA   -11.55mA
-821mV    -7.603mA   -7.856mA   -9.113mA
-754mV    -5.655mA   -5.623mA   -6.821mA
-620mV    -2.371mA   -2.616mA   -2.797mA
-553mV    -1.172mA   -1.518mA   -1.313mA
-486mV    -396.2uA   -716.4uA   -376.4uA
-419mV    -71.95uA   -244.9uA   -42.84uA
3.3V      0A         0A         0A
[POWER_clamp]
|Voltage   I(typ)   I(min)   I(max)
-3.266V   2.002A     2.005A     2.003A
-1.122V   95.84mA    122.3mA    80.75mA
-1.055V   56.42mA    81.13mA    43.84mA
-988mV    29.46mA    48.05mA    24.15mA
-921mV    16.84mA    25.99mA    17.71mA
-854mV    12.12mA    14.6mA     14.67mA
-787mV    9.585mA    9.535mA    12.12mA
-720mV    7.529mA    6.931mA    9.676mA
-519mV    2.487mA    2.496mA    3.276mA
-385mV    477.3uA    731.6uA    579.8uA
-184mV    1.009uA    11.15uA    276.7nA
3.3V      0A         0A         0A
[Ramp]
| variable   typ   min   max
dV/dt_r   1.007/3.438n   0.891/3.757n   1.145/3.345n
dV/dt_f   1.007/3.388n   0.899/3.606n   1.141/3.345n
R_load = 50.000
[Rising Waveform]
R_fixture = 50.000
V_fixture = 0.000
V_fixture_min = 0.000
V_fixture_max = 0.000
|  time   V(typ)   V(min)   V(max)
0s        2.509uV    9.592uV    933.5nV
2.09ns    2.902mV    4.884mV    6.711mV
2.944ns   64.02mV    55.33mV    103.5mV
4.364ns   353.1mV    271.8mV    493mV
6.301ns   940.4mV    734.6mV    1.201V
7.174ns   1.196V     958.1mV    1.459V
8.36ns    1.421V     1.188V     1.672V
9.945ns   1.544V     1.329V     1.783V
17ns      1.636V     1.444V     1.863V
50ns      1.644V     1.454V     1.87V
[Rising Waveform]
R_fixture = 50.000
V_fixture = 3.300
V_fixture_min = 3.200
V_fixture_max = 3.400
|  time   V(typ)   V(min)   V(max)
0s        1.655V     1.732V     1.536V
434ps     1.656V     1.733V     1.572V
540ps     1.73V      1.732V     2.337V
630ps     2.315V     1.782V     2.83V
699ps     2.684V     2.097V     3.034V
780ps     2.93V      2.541V     3.173V
880ps     3.092V     2.845V     3.268V
1.009ns   3.194V     3.027V     3.33V
1.451ns   3.287V     3.179V     3.391V
50ns      3.3V       3.2V       3.4V
[Falling Waveform]
R_fixture = 50.000
V_fixture = 3.300
V_fixture_min = 3.200
V_fixture_max = 3.400
|  time   V(typ)   V(min)   V(max)
0s        3.3V       3.2V       3.4V
2.707ns   3.296V     3.193V     3.394V
3.641ns   3.236V     3.136V     3.309V
5.067ns   2.951V     2.902V     2.943V
7.232ns   2.284V     2.351V     2.159V
7.967ns   2.074V     2.164V     1.948V
9.193ns   1.858V     1.947V     1.737V
10.87ns   1.736V     1.822V     1.615V
16.78ns   1.663V     1.741V     1.545V
50ns      1.655V     1.732V     1.536V
[Falling Waveform]
R_fixture = 50.000
V_fixture = 0.000
V_fixture_min = 0.000
V_fixture_max = 0.000
|  time   V(typ)   V(min)   V(max)
0s        1.644V     1.454V     1.87V
505ps     1.644V     1.454V     1.829V
546ps     1.642V     1.454V     1.677V
625ps     1.566V     1.455V     1.078V
702ps     1.153V     1.428V     660.4mV
833ps     514.8mV    964.1mV    294.8mV
923ps     300.1mV    566.6mV    172.2mV
1.027ns   162.7mV    306.4mV    93.87mV
1.491ns   12.23mV    22.49mV    7.312mV
50ns      2.509uV    9.592uV    933nV
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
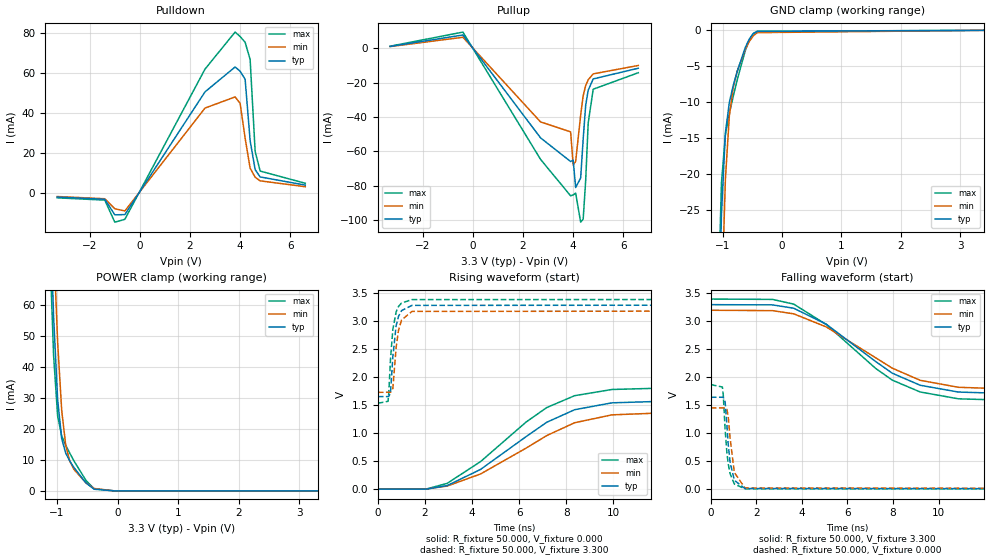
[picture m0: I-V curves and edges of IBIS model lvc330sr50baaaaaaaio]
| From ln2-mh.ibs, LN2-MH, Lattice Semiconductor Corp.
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|   Model lvc330sr50baaaaaaaio
[Model] lvc330sr50baaaaaaaio
Model_type I/O
Polarity   Non-Inverting
Enable   Active-Low
Vinl =  0.800V
Vinh =  2.000V
Vmeas =  1.650V
Cref =  0.0F
Rref =  1.000M
Vref =  0.0V
C_comp   2.000pF   1.500pF   2.500pF
[Temperature Range]   25.000   0.125k   -40.000
[Voltage Range]   3.300V   3.200V   3.400V
[C Comp Corner]
C_comp   2.000pF   1.500pF   2.500pF
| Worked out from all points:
|   slope of the pulldown table from 0 to 0.495 V, typ, clamps not added: 49.7 ohm
|   slope of the pullup table from 0 to 0.495 V, typ, clamps not added: 50.2 ohm
|   GND clamp passes 1 mA (typ) near -0.53 V on its own axis
|   POWER clamp passes 1 mA (typ) near -0.42 V on its own axis
|   rising waveform, R_fixture 50.000, V_fixture 0.000: 20-80 % time 3.43ns typ, 3.74ns min, 3.34ns max; typ from 0 V to 1.64 V
|   rising waveform, R_fixture 50.000, V_fixture 3.300: 20-80 % time 216ps typ, 226ps min, 208ps max; typ from 1.66 V to 3.3 V
|   falling waveform, R_fixture 50.000, V_fixture 3.300: 20-80 % time 3.39ns typ, 3.6ns min, 3.35ns max; typ from 3.3 V to 1.66 V
|   falling waveform, R_fixture 50.000, V_fixture 0.000: 20-80 % time 230ps typ, 242ps min, 222ps max; typ from 1.64 V to 0 V
[Pulldown]
|Voltage   I(typ)   I(min)   I(max)
-3.3V     -1.986mA   -1.719mA   -2.369mA
-1.4V     -3.1mA     -2.834mA   -3.514mA
-1V       -10.86mA   -7.831mA   -14.54mA
-600mV    -10.75mA   -8.931mA   -13.11mA
2.6V      50.55mA    42.46mA    61.92mA
3.8V      62.96mA    48.01mA    80.39mA
4V        60.86mA    44.85mA    78.2mA
4.2V      56.87mA    27.45mA    75.3mA
4.4V      26.18mA    12.43mA    66.69mA
4.6V      11.71mA    7.915mA    20.83mA
4.8V      8.062mA    6.099mA    10.99mA
6.6V      3.979mA    3.184mA    4.897mA
[Pullup]
|Voltage   I(typ)   I(min)   I(max)
-3.3V     934.3uA    841.6uA    1.075mA
-400mV    7.568mA    6.235mA    9.245mA
2.7V      -52.1mA    -42.86mA   -64.59mA
3.9V      -65.83mA   -48.62mA   -85.71mA
4V        -64.91mA   -67.77mA   -85.22mA
4.1V      -80.89mA   -65.78mA   -84.13mA
4.3V      -75.32mA   -38.93mA   -101mA
4.4V      -52.83mA   -27.68mA   -99.21mA
4.5V      -33.23mA   -21.77mA   -76.82mA
4.6V      -24.51mA   -18.44mA   -43.55mA
4.8V      -17.92mA   -14.99mA   -23.89mA
6.6V      -11.71mA   -10.11mA   -14.32mA
[GND_clamp]
|Voltage   I(typ)   I(min)   I(max)
-3.3V     -1.861A    -1.855A    -1.868A
-1.089V   -50.81mA   -68.21mA   -41.78mA
-1.022V   -25.75mA   -39.09mA   -21.32mA
-955mV    -14.27mA   -20.74mA   -14.55mA
-888mV    -9.999mA   -11.85mA   -11.57mA
-821mV    -7.623mA   -7.877mA   -9.132mA
-754mV    -5.679mA   -5.648mA   -6.844mA
-620mV    -2.407mA   -2.651mA   -2.831mA
-553mV    -1.221mA   -1.563mA   -1.361mA
-486mV    -463.6uA   -775.1uA   -445.5uA
-419mV    -157.8uA   -320.2uA   -132.1uA
3.4V      0A         0A         0A
[POWER_clamp]
|Voltage   I(typ)   I(min)   I(max)
-3.266V   2.002A     2.005A     2.003A
-1.122V   95.85mA    122.4mA    80.77mA
-1.055V   56.44mA    81.14mA    43.86mA
-988mV    29.49mA    48.07mA    24.19mA
-921mV    16.88mA    26.01mA    17.76mA
-854mV    12.16mA    14.63mA    14.72mA
-787mV    9.627mA    9.57mA     12.17mA
-720mV    7.572mA    6.968mA    9.725mA
-519mV    2.543mA    2.542mA    3.339mA
-385mV    550.4uA    786uA      665.7uA
-50mV     13.15uA    11.69uA    15.71uA
3.3V      0A         0A         0A
[Ramp]
| variable   typ   min   max
dV/dt_r   1.007/3.435n   0.891/3.757n   1.145/3.345n
dV/dt_f   1.007/3.394n   0.899/3.600n   1.141/3.347n
R_load = 50.000
[Rising Waveform]
R_fixture = 50.000
V_fixture = 0.000
V_fixture_min = 0.000
V_fixture_max = 0.000
|  time   V(typ)   V(min)   V(max)
0s        2.51uV     9.59uV     935nV
2.09ns    2.903mV    4.883mV    6.719mV
2.944ns   64.02mV    55.33mV    103.5mV
4.364ns   353.1mV    271.8mV    493.1mV
6.3ns     940.1mV    734.4mV    1.201V
7.174ns   1.196V     958.1mV    1.459V
8.36ns    1.421V     1.188V     1.672V
9.945ns   1.544V     1.329V     1.783V
17ns      1.636V     1.444V     1.863V
50ns      1.644V     1.454V     1.87V
[Rising Waveform]
R_fixture = 50.000
V_fixture = 3.300
V_fixture_min = 3.200
V_fixture_max = 3.400
|  time   V(typ)   V(min)   V(max)
0s        1.655V     1.732V     1.536V
434ps     1.656V     1.733V     1.571V
464ps     1.655V     1.733V     1.705V
540ps     1.73V      1.732V     2.335V
638ps     2.366V     1.801V     2.858V
779ps     2.928V     2.537V     3.171V
878ps     3.09V      2.841V     3.266V
1.008ns   3.193V     3.026V     3.33V
1.449ns   3.287V     3.179V     3.39V
50ns      3.3V       3.2V       3.4V
[Falling Waveform]
R_fixture = 50.000
V_fixture = 3.300
V_fixture_min = 3.200
V_fixture_max = 3.400
|  time   V(typ)   V(min)   V(max)
0s        3.3V       3.2V       3.4V
2.707ns   3.296V     3.193V     3.394V
3.637ns   3.236V     3.136V     3.31V
5.067ns   2.951V     2.902V     2.945V
7.237ns   2.283V     2.35V      2.16V
7.967ns   2.074V     2.164V     1.95V
9.194ns   1.858V     1.947V     1.738V
10.87ns   1.737V     1.822V     1.616V
16.79ns   1.663V     1.741V     1.545V
50ns      1.655V     1.732V     1.536V
[Falling Waveform]
R_fixture = 50.000
V_fixture = 0.000
V_fixture_min = 0.000
V_fixture_max = 0.000
|  time   V(typ)   V(min)   V(max)
0s        1.644V     1.454V     1.87V
506ps     1.644V     1.454V     1.827V
546ps     1.643V     1.454V     1.678V
626ps     1.564V     1.454V     1.072V
702ps     1.154V     1.428V     661.1mV
762ps     800.9mV    1.306V     456mV
842ps     488mV      918.9mV    279.4mV
1.032ns   158.2mV    297.8mV    91.29mV
1.498ns   11.8mV     21.67mV    7.064mV
50ns      2.51uV     9.59uV     934.5nV
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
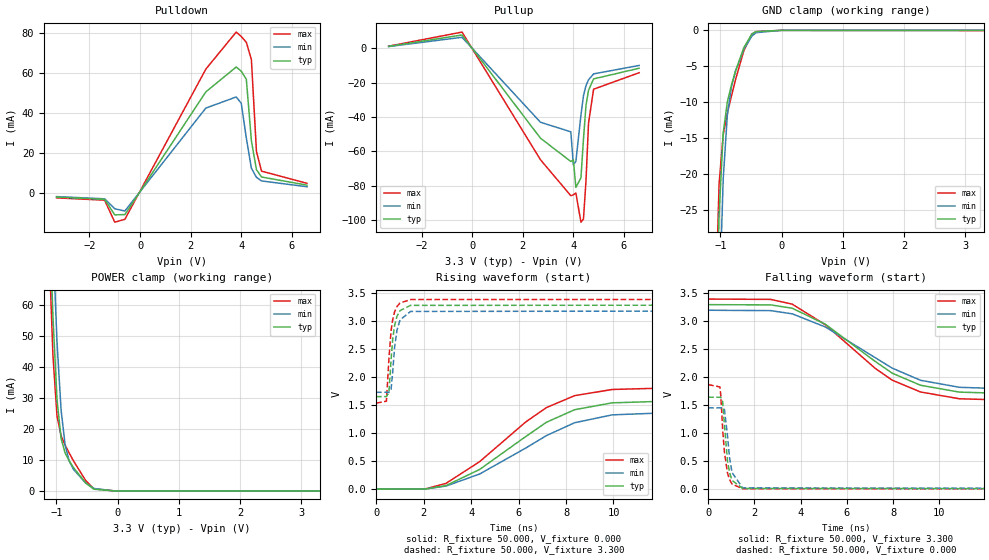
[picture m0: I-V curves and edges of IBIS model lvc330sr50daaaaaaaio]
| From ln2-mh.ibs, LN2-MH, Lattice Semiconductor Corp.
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|   Model lvc330sr50daaaaaaaio
[Model] lvc330sr50daaaaaaaio
Model_type I/O
Polarity   Non-Inverting
Enable   Active-Low
Vinl =  0.800V
Vinh =  2.000V
Vmeas =  1.650V
Cref =  0.0F
Rref =  1.000M
Vref =  0.0V
C_comp   2.000pF   1.500pF   2.500pF
[Temperature Range]   25.000   0.125k   -40.000
[Voltage Range]   3.300V   3.200V   3.400V
[C Comp Corner]
C_comp   2.000pF   1.500pF   2.500pF
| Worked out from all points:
|   slope of the pulldown table from 0 to 0.495 V, typ, clamps not added: 50.1 ohm
|   slope of the pullup table from 0 to 0.495 V, typ, clamps not added: 50.2 ohm
|   GND clamp passes 1 mA (typ) near -0.53 V on its own axis
|   POWER clamp passes 1 mA (typ) near -0.42 V on its own axis
|   rising waveform, R_fixture 50.000, V_fixture 0.000: 20-80 % time 3.43ns typ, 3.74ns min, 3.34ns max; typ from 0 V to 1.64 V
|   rising waveform, R_fixture 50.000, V_fixture 3.300: 20-80 % time 216ps typ, 226ps min, 208ps max; typ from 1.66 V to 3.3 V
|   falling waveform, R_fixture 50.000, V_fixture 3.300: 20-80 % time 3.39ns typ, 3.6ns min, 3.35ns max; typ from 3.3 V to 1.66 V
|   falling waveform, R_fixture 50.000, V_fixture 0.000: 20-80 % time 230ps typ, 242ps min, 222ps max; typ from 1.64 V to 0 V
[Pulldown]
|Voltage   I(typ)   I(min)   I(max)
-3.3V     -1.981mA   -1.715mA   -2.363mA
-1.4V     -3.092mA   -2.827mA   -3.505mA
-1V       -10.83mA   -7.812mA   -14.5mA
-600mV    -10.71mA   -8.906mA   -13.05mA
2.6V      50.55mA    42.46mA    61.92mA
3.8V      62.96mA    48.01mA    80.39mA
4V        60.86mA    44.85mA    78.2mA
4.2V      56.87mA    27.45mA    75.3mA
4.4V      26.18mA    12.43mA    66.69mA
4.6V      11.71mA    7.915mA    20.83mA
4.8V      8.062mA    6.099mA    10.99mA
6.6V      3.979mA    3.184mA    4.897mA
[Pullup]
|Voltage   I(typ)   I(min)   I(max)
-3.3V     934.3uA    841.6uA    1.075mA
-400mV    7.568mA    6.235mA    9.245mA
2.7V      -52.28mA   -43.04mA   -64.77mA
3.9V      -65.8mA    -48.59mA   -85.65mA
4V        -64.88mA   -67.74mA   -85.16mA
4.1V      -80.85mA   -65.75mA   -84.08mA
4.3V      -75.29mA   -38.91mA   -101mA
4.4V      -52.81mA   -27.67mA   -99.16mA
4.5V      -33.21mA   -21.77mA   -76.79mA
4.6V      -24.5mA    -18.43mA   -43.54mA
4.8V      -17.91mA   -14.99mA   -23.88mA
6.6V      -11.71mA   -10.11mA   -14.32mA
[GND_clamp]
|Voltage   I(typ)   I(min)   I(max)
-3.3V     -1.861A    -1.855A    -1.868A
-1.089V   -50.83mA   -68.22mA   -41.81mA
-1.022V   -25.77mA   -39.11mA   -21.36mA
-955mV    -14.31mA   -20.77mA   -14.6mA
-888mV    -10.03mA   -11.88mA   -11.61mA
-821mV    -7.659mA   -7.903mA   -9.179mA
-754mV    -5.715mA   -5.674mA   -6.892mA
-620mV    -2.446mA   -2.677mA   -2.886mA
-486mV    -500.9uA   -793.7uA   -505.5uA
-419mV    -184.7uA   -329.9uA   -181.9uA
-17mV     -4.77uA    -4.625uA   -5.541uA
3.3V      -213nA     0A         -30.51uA
[POWER_clamp]
|Voltage   I(typ)   I(min)   I(max)
-3.266V   2.002A     2.005A     2.003A
-1.122V   95.85mA    122.4mA    80.77mA
-1.055V   56.44mA    81.14mA    43.86mA
-988mV    29.49mA    48.07mA    24.19mA
-921mV    16.88mA    26.01mA    17.76mA
-854mV    12.16mA    14.63mA    14.72mA
-787mV    9.627mA    9.57mA     12.17mA
-720mV    7.572mA    6.968mA    9.725mA
-519mV    2.543mA    2.542mA    3.339mA
-385mV    550.4uA    786uA      665.7uA
-50mV     13.15uA    11.69uA    15.71uA
3.3V      0A         0A         30.92uA
[Ramp]
| variable   typ   min   max
dV/dt_r   1.007/3.439n   0.891/3.757n   1.145/3.344n
dV/dt_f   1.007/3.393n   0.899/3.602n   1.141/3.347n
R_load = 50.000
[Rising Waveform]
R_fixture = 50.000
V_fixture = 0.000
V_fixture_min = 0.000
V_fixture_max = 0.000
|  time   V(typ)   V(min)   V(max)
0s        87.51uV    -11.28uV   36.1uV
2.09ns    2.987mV    4.862mV    6.751mV
2.944ns   64.1mV     55.31mV    103.6mV
4.364ns   353.1mV    271.7mV    493.1mV
6.3ns     940.2mV    734.4mV    1.201V
7.174ns   1.196V     958.1mV    1.459V
8.36ns    1.421V     1.188V     1.672V
9.946ns   1.544V     1.329V     1.783V
16.99ns   1.636V     1.444V     1.863V
50ns      1.644V     1.454V     1.87V
[Rising Waveform]
R_fixture = 50.000
V_fixture = 3.300
V_fixture_min = 3.200
V_fixture_max = 3.400
|  time   V(typ)   V(min)   V(max)
0s        1.655V     1.732V     1.538V
434ps     1.656V     1.733V     1.573V
540ps     1.73V      1.732V     2.336V
630ps     2.315V     1.782V     2.83V
699ps     2.684V     2.097V     3.034V
780ps     2.93V      2.541V     3.173V
880ps     3.092V     2.845V     3.267V
1.009ns   3.194V     3.027V     3.33V
1.451ns   3.287V     3.179V     3.391V
50ns      3.3V       3.2V       3.4V
[Falling Waveform]
R_fixture = 50.000
V_fixture = 3.300
V_fixture_min = 3.200
V_fixture_max = 3.400
|  time   V(typ)   V(min)   V(max)
0s        3.3V       3.2V       3.4V
2.707ns   3.296V     3.193V     3.394V
3.637ns   3.236V     3.136V     3.309V
5.067ns   2.951V     2.902V     2.942V
7.229ns   2.285V     2.352V     2.161V
7.967ns   2.074V     2.164V     1.949V
9.194ns   1.858V     1.947V     1.738V
10.87ns   1.736V     1.822V     1.617V
16.78ns   1.663V     1.741V     1.546V
50ns      1.655V     1.732V     1.538V
[Falling Waveform]
R_fixture = 50.000
V_fixture = 0.000
V_fixture_min = 0.000
V_fixture_max = 0.000
|  time   V(typ)   V(min)   V(max)
0s        1.644V     1.454V     1.87V
505ps     1.644V     1.454V     1.829V
546ps     1.642V     1.454V     1.677V
626ps     1.563V     1.454V     1.071V
702ps     1.153V     1.428V     660.4mV
834ps     511.7mV    959.6mV    293mV
922ps     302mV      570.4mV    173.2mV
1.032ns   158.1mV    297.7mV    91.24mV
1.491ns   12.32mV    22.49mV    7.346mV
50ns      87.51uV    -11.28uV   36.1uV
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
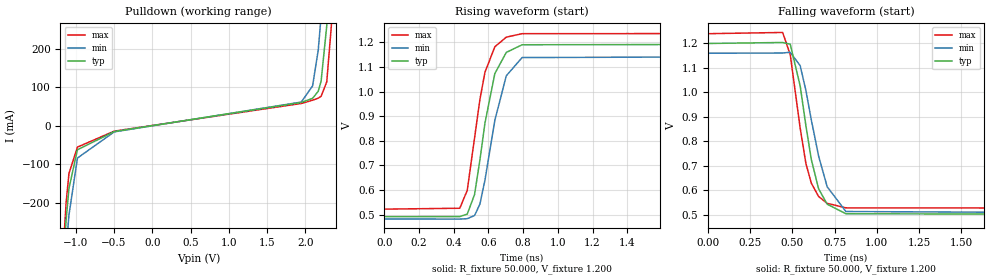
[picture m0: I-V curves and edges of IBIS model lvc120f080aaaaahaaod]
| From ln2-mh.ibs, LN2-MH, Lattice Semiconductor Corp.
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|   Model lvc120f080aaaaahaaod
[Model] lvc120f080aaaaahaaod
Model_type Open_drain
Polarity   Non-Inverting
Enable   Active-High
Vmeas =  0.600V
Cref =  0.0F
Rref =  1000
Vref =  1.20V
C_comp   2.000pF   1.500pF   2.500pF
[Temperature Range]   25.000   0.125k   -40.000
[Voltage Range]   1.200V   1.160V   1.240V
[C Comp Corner]
C_comp   2.000pF   1.500pF   2.500pF
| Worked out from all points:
|   slope of the pulldown table from 0 to 0.18 V, typ, clamps not added: 34.6 ohm
|   rising waveform, R_fixture 50.000, V_fixture 1.200: 20-80 % time 97.3ps typ, 108ps min, 92.3ps max; typ from 0.492 V to 1.2 V
|   falling waveform, R_fixture 50.000, V_fixture 1.200: 20-80 % time 103ps typ, 129ps min, 94.9ps max; typ from 1.2 V to 0.492 V
[Pulldown]
|Voltage   I(typ)   I(min)   I(max)
-1.2V     -480.2mA   -553.3mA   -441.4mA
-1.126V   -245.7mA   -322.4mA   -200.6mA
-1.089V   -163.2mA   -232.5mA   -124.2mA
-978mV    -62.48mA   -84.09mA   -55.58mA
-497mV    -15.11mA   -15.9mA    -13.96mA
1.945V    60.66mA    61.67mA    58.03mA
2.093V    71.39mA    103.9mA    66.59mA
2.167V    89.91mA    197.7mA    71.94mA
2.204V    116.1mA    285.8mA    76.73mA
2.278V    260.7mA    554.7mA    114.5mA
2.352V    562mA      921.4mA    294.8mA
2.4V      814.8mA    1.192A     507mA
[Ramp]
| variable   typ   min   max
dV/dt_r   0.425/0.123n   0.407/0.139n   0.418/0.113n
dV/dt_f   0.425/0.104n   0.407/0.129n   0.431/94.885p
R_load = 50.000
[Rising Waveform]
R_fixture= 50.000
V_fixture= 1.200
V_fixture_min= 1.160
V_fixture_max= 1.240
|time   V(typ)   V(min)   V(max)
0s        491.7mV    482.1mV    522.1mV
435ps     491.9mV    481.8mV    525.7mV
478ps     501.9mV    483.3mV    598.4mV
520ps     581.1mV    496.1mV    810.6mV
551ps     722mV      542.7mV    968mV
580ps     871.5mV    639.8mV    1.078V
637ps     1.073V     883mV      1.182V
703ps     1.159V     1.064V     1.221V
794ps     1.19V      1.138V     1.235V
10ns      1.2V       1.16V      1.24V
[Falling Waveform]
R_fixture= 50.000
V_fixture= 1.200
V_fixture_min= 1.160
V_fixture_max= 1.240
|time   V(typ)   V(min)   V(max)
0s        1.2V       1.16V      1.24V
442ps     1.204V     1.161V     1.245V
487ps     1.197V     1.164V     1.154V
546ps     1.026V     1.109V     853.5mV
580ps     863.1mV    1.007V     708.6mV
612ps     725.1mV    887.1mV    628.7mV
655ps     605.9mV    740mV      574.6mV
706ps     542.8mV    614.1mV    546.4mV
817ps     503.7mV    512.9mV    527.9mV
10ns      491.7mV    482.1mV    522.1mV
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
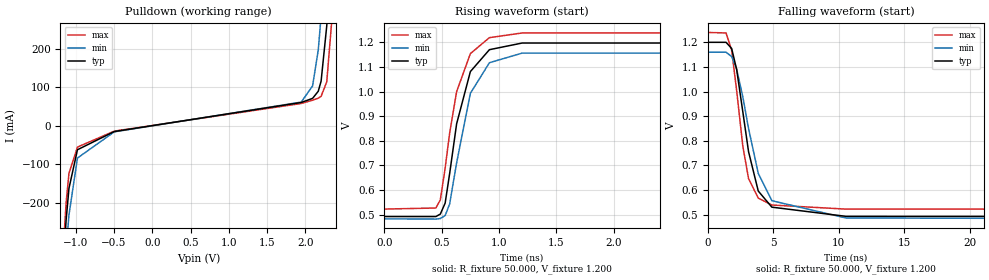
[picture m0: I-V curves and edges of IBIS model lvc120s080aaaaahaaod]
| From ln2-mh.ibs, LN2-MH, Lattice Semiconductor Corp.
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|   Model lvc120s080aaaaahaaod
[Model] lvc120s080aaaaahaaod
Model_type Open_drain
Polarity   Non-Inverting
Enable   Active-High
Vmeas =  0.600V
Cref =  0.0F
Rref =  1000
Vref =  1.20V
C_comp   2.000pF   1.500pF   2.500pF
[Temperature Range]   25.000   0.125k   -40.000
[Voltage Range]   1.200V   1.160V   1.240V
[C Comp Corner]
C_comp   2.000pF   1.500pF   2.500pF
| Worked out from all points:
|   slope of the pulldown table from 0 to 0.18 V, typ, clamps not added: 34.6 ohm
|   rising waveform, R_fixture 50.000, V_fixture 1.200: 20-80 % time 170ps typ, 177ps min, 167ps max; typ from 0.492 V to 1.2 V
|   falling waveform, R_fixture 50.000, V_fixture 1.200: 20-80 % time 1.31ns typ, 1.68ns min, 1.02ns max; typ from 1.2 V to 0.492 V
[Pulldown]
|Voltage   I(typ)   I(min)   I(max)
-1.2V     -480.2mA   -553.3mA   -441.4mA
-1.126V   -245.7mA   -322.4mA   -200.6mA
-1.089V   -163.2mA   -232.5mA   -124.2mA
-978mV    -62.48mA   -84.09mA   -55.58mA
-497mV    -15.11mA   -15.9mA    -13.96mA
1.945V    60.66mA    61.66mA    58.03mA
2.093V    71.39mA    103.9mA    66.59mA
2.167V    89.91mA    197.7mA    71.94mA
2.204V    116.1mA    285.8mA    76.73mA
2.278V    260.7mA    554.7mA    114.5mA
2.352V    562mA      921.4mA    294.8mA
2.4V      814.8mA    1.192A     507mA
[Ramp]
| variable   typ   min   max
dV/dt_r   0.425/1.495n   0.407/1.954n   0.418/1.198n
dV/dt_f   0.425/1.311n   0.407/1.683n   0.431/1.025n
R_load = 50.000
[Rising Waveform]
R_fixture= 50.000
V_fixture= 1.200
V_fixture_min= 1.160
V_fixture_max= 1.240
|time   V(typ)   V(min)   V(max)
0s        491.7mV    482.2mV    522.1mV
450ps     491.7mV    481.5mV    526.4mV
489ps     501.8mV    483.6mV    559.7mV
531ps     546.5mV    495.8mV    688.7mV
570ps     665.7mV    542.5mV    830.3mV
631ps     868.7mV    710mV      999.5mV
751ps     1.081V     992.8mV    1.154V
917ps     1.17V      1.117V     1.219V
1.202ns   1.197V     1.156V     1.238V
50ns      1.2V       1.16V      1.24V
[Falling Waveform]
R_fixture= 50.000
V_fixture= 1.200
V_fixture_min= 1.160
V_fixture_max= 1.240
|time   V(typ)   V(min)   V(max)
0s        1.2V       1.16V      1.24V
1.373ns   1.2V       1.16V      1.238V
1.802ns   1.175V     1.142V     1.168V
2.183ns   1.09V      1.091V     1.005V
2.656ns   917.7mV    978.6mV    777.9mV
3.093ns   756.2mV    850.2mV    646.8mV
3.836ns   595.9mV    667.9mV    567.2mV
4.877ns   530.4mV    556.6mV    539.1mV
10.54ns   493.1mV    486.4mV    522.5mV
50ns      491.7mV    482.1mV    522.1mV
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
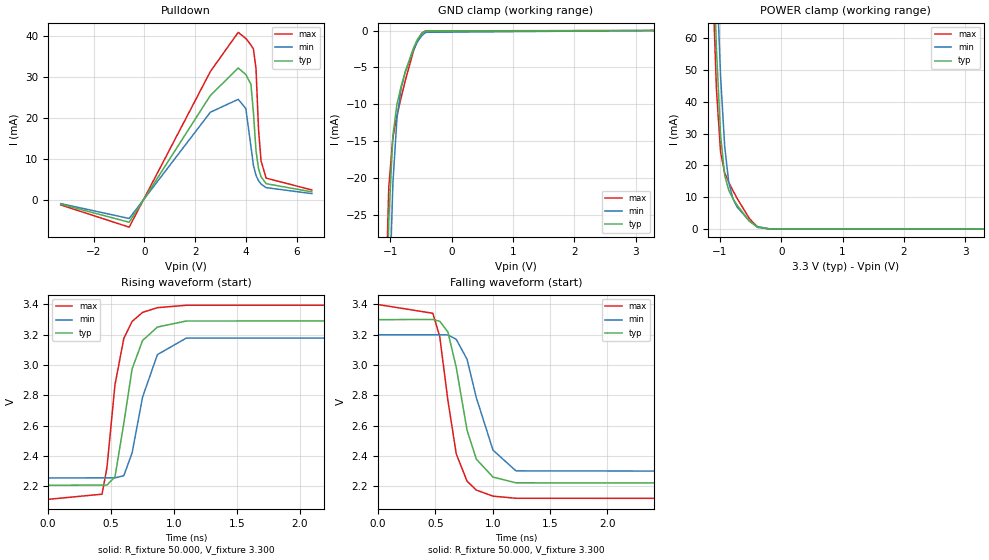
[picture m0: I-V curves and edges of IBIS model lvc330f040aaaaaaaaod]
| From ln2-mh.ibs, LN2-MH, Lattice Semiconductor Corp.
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|   Model lvc330f040aaaaaaaaod
[Model] lvc330f040aaaaaaaaod
Model_type I/O_open_drain
Polarity   Non-Inverting
Enable   Active-Low
Vinl =  0.800V
Vinh =  2.000V
Vmeas =  1.650V
Cref =  0.0F
Rref =  1000
Vref =  3.30V
C_comp   2.000pF   1.500pF   2.500pF
[Temperature Range]   25.000   0.125k   -40.000
[Voltage Range]   3.300V   3.200V   3.400V
[C Comp Corner]
C_comp   2.000pF   1.500pF   2.500pF
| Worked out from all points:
|   slope of the pulldown table from 0 to 0.495 V, typ, clamps not added: 98.5 ohm
|   GND clamp passes 1 mA (typ) near -0.54 V on its own axis
|   POWER clamp passes 1 mA (typ) near -0.43 V on its own axis
|   rising waveform, R_fixture 50.000, V_fixture 3.300: 20-80 % time 133ps typ, 155ps min, 115ps max; typ from 2.21 V to 3.3 V
|   falling waveform, R_fixture 50.000, V_fixture 3.300: 20-80 % time 171ps typ, 212ps min, 149ps max; typ from 3.3 V to 2.21 V
[Pulldown]
|Voltage   I(typ)   I(min)   I(max)
-3.3V     -991.1uA   -858.3uA   -1.183mA
-600mV    -5.406mA   -4.489mA   -6.6mA
2.6V      25.49mA    21.41mA    31.32mA
3.7V      32.19mA    24.56mA    40.89mA
4V        30.59mA    22.3mA     39.39mA
4.2V      28.23mA    13.08mA    37.81mA
4.3V      21.31mA    8.471mA    36.8mA
4.4V      12.1mA     6.034mA    32.08mA
4.5V      7.681mA    4.709mA    17.27mA
4.6V      5.686mA    3.907mA    9.552mA
4.8V      3.997mA    3.033mA    5.35mA
6.6V      2.008mA    1.58mA     2.473mA
[GND_clamp]
|Voltage   I(typ)   I(min)   I(max)
-3.3V     -1.861A    -1.855A    -1.868A
-1.089V   -50.81mA   -68.2mA    -41.77mA
-1.022V   -25.74mA   -39.08mA   -21.31mA
-955mV    -14.26mA   -20.73mA   -14.54mA
-888mV    -9.982mA   -11.84mA   -11.55mA
-821mV    -7.603mA   -7.856mA   -9.113mA
-754mV    -5.655mA   -5.623mA   -6.821mA
-620mV    -2.371mA   -2.616mA   -2.797mA
-553mV    -1.172mA   -1.518mA   -1.313mA
-486mV    -396.2uA   -716.4uA   -376.4uA
-419mV    -71.95uA   -244.9uA   -42.84uA
3.3V      0A         0A         0A
[POWER_clamp]
|Voltage   I(typ)   I(min)   I(max)
-3.266V   2.002A     2.005A     2.003A
-1.122V   95.84mA    122.3mA    80.75mA
-1.055V   56.42mA    81.13mA    43.84mA
-988mV    29.46mA    48.05mA    24.15mA
-921mV    16.84mA    25.99mA    17.71mA
-854mV    12.12mA    14.6mA     14.67mA
-787mV    9.585mA    9.535mA    12.12mA
-720mV    7.529mA    6.931mA    9.676mA
-519mV    2.487mA    2.496mA    3.276mA
-385mV    477.3uA    731.6uA    579.8uA
-184mV    1.009uA    11.15uA    276.7nA
3.3V      0A         0A         0A
[Ramp]
| variable   typ   min   max
dV/dt_r   0.669/0.196n   0.572/0.247n   0.790/0.168n
dV/dt_f   0.670/0.172n   0.580/0.213n   0.788/0.150n
R_load = 50.000
[Rising Waveform]
R_fixture = 50.000
V_fixture = 3.300
V_fixture_min = 3.200
V_fixture_max = 3.400
|  time   V(typ)   V(min)   V(max)
0s        2.206V     2.254V     2.113V
428ps     2.207V     2.255V     2.147V
467ps     2.207V     2.255V     2.322V
531ps     2.262V     2.255V     2.87V
601ps     2.615V     2.269V     3.176V
667ps     2.975V     2.42V      3.288V
750ps     3.162V     2.788V     3.348V
868ps     3.251V     3.069V     3.379V
1.097ns   3.291V     3.178V     3.395V
50ns      3.3V       3.2V       3.4V
[Falling Waveform]
R_fixture = 50.000
V_fixture = 3.300
V_fixture_min = 3.200
V_fixture_max = 3.400
|  time   V(typ)   V(min)   V(max)
0s        3.3V       3.2V       3.4V
479ps     3.301V     3.2V       3.342V
539ps     3.289V     3.2V       3.188V
610ps     3.219V     3.199V     2.768V
683ps     2.984V     3.17V      2.413V
777ps     2.57V      3.038V     2.233V
858ps     2.378V     2.784V     2.174V
1.003ns   2.26V      2.438V     2.134V
1.203ns   2.222V     2.301V     2.12V
50ns      2.206V     2.254V     2.113V
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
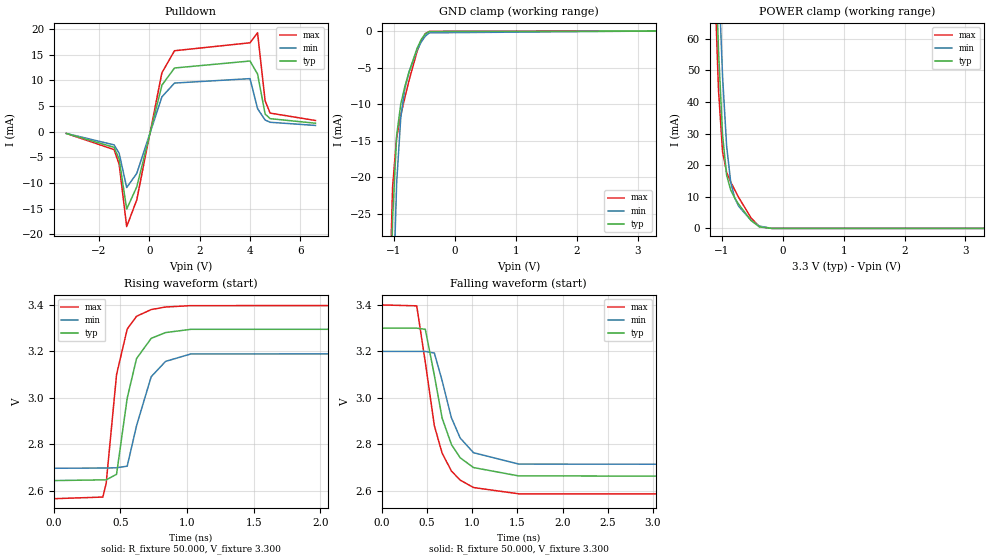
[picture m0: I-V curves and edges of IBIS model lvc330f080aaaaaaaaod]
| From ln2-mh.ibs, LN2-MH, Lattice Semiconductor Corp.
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|   Model lvc330f080aaaaaaaaod
[Model] lvc330f080aaaaaaaaod
Model_type I/O_open_drain
Polarity   Non-Inverting
Enable   Active-Low
Vinl =  0.800V
Vinh =  2.000V
Vmeas =  1.650V
Cref =  0.0F
Rref =  1000
Vref =  3.30V
C_comp   2.000pF   1.500pF   2.500pF
[Temperature Range]   25.000   0.125k   -40.000
[Voltage Range]   3.300V   3.200V   3.400V
[C Comp Corner]
C_comp   2.000pF   1.500pF   2.500pF
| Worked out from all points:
|   slope of the pulldown table from 0 to 0.495 V, typ, clamps not added: 55.2 ohm
|   GND clamp passes 1 mA (typ) near -0.54 V on its own axis
|   POWER clamp passes 1 mA (typ) near -0.43 V on its own axis
|   rising waveform, R_fixture 50.000, V_fixture 3.300: 20-80 % time 122ps typ, 146ps min, 103ps max; typ from 2.64 V to 3.3 V
|   falling waveform, R_fixture 50.000, V_fixture 3.300: 20-80 % time 255ps typ, 271ps min, 245ps max; typ from 3.3 V to 2.64 V
[Pulldown]
|Voltage   I(typ)   I(min)   I(max)
-3.3V     -352.1uA   -351uA     -351.1uA
-1.4V     -3.051mA   -2.583mA   -3.502mA
-1.2V     -5.34mA    -4.2mA     -6.367mA
-900mV    -15.08mA   -10.89mA   -18.49mA
-500mV    -10.76mA   -8.133mA   -13.29mA
500mV     9.049mA    6.78mA     11.47mA
1V        12.39mA    9.457mA    15.75mA
4V        13.75mA    10.32mA    17.3mA
4.3V      11.21mA    4.481mA    19.24mA
4.6V      3.439mA    2.258mA    5.994mA
4.8V      2.525mA    1.821mA    3.608mA
6.6V      1.635mA    1.206mA    2.169mA
[GND_clamp]
|Voltage   I(typ)   I(min)   I(max)
-3.3V     -1.861A    -1.855A    -1.868A
-1.089V   -50.81mA   -68.2mA    -41.77mA
-1.022V   -25.74mA   -39.08mA   -21.31mA
-955mV    -14.26mA   -20.73mA   -14.54mA
-888mV    -9.982mA   -11.84mA   -11.55mA
-821mV    -7.603mA   -7.856mA   -9.113mA
-754mV    -5.655mA   -5.623mA   -6.821mA
-620mV    -2.371mA   -2.616mA   -2.797mA
-553mV    -1.172mA   -1.518mA   -1.313mA
-486mV    -396.2uA   -716.4uA   -376.4uA
-419mV    -71.95uA   -244.9uA   -42.84uA
3.3V      0A         0A         0A
[POWER_clamp]
|Voltage   I(typ)   I(min)   I(max)
-3.266V   2.002A     2.005A     2.003A
-1.122V   95.84mA    122.3mA    80.75mA
-1.055V   56.42mA    81.13mA    43.84mA
-988mV    29.46mA    48.05mA    24.15mA
-921mV    16.84mA    25.99mA    17.71mA
-854mV    12.12mA    14.6mA     14.67mA
-787mV    9.585mA    9.535mA    12.12mA
-720mV    7.529mA    6.931mA    9.676mA
-519mV    2.487mA    2.496mA    3.276mA
-385mV    477.3uA    731.6uA    579.8uA
-184mV    1.009uA    11.15uA    276.7nA
3.3V      0A         0A         0A
[Ramp]
| variable   typ   min   max
dV/dt_r   0.394/0.282n   0.302/0.294n   0.500/0.273n
dV/dt_f   0.403/0.255n   0.310/0.272n   0.511/0.244n
R_load = 50.000
[Rising Waveform]
R_fixture = 50.000
V_fixture = 3.300
V_fixture_min = 3.200
V_fixture_max = 3.400
|  time   V(typ)   V(min)   V(max)
0s        2.644V     2.697V     2.566V
368ps     2.647V     2.698V     2.573V
393ps     2.647V     2.698V     2.632V
471ps     2.671V     2.699V     3.1V
551ps     2.999V     2.706V     3.296V
621ps     3.169V     2.88V      3.351V
731ps     3.256V     3.091V     3.38V
839ps     3.281V     3.157V     3.391V
1.029ns   3.295V     3.189V     3.397V
50ns      3.3V       3.2V       3.4V
[Falling Waveform]
R_fixture = 50.000
V_fixture = 3.300
V_fixture_min = 3.200
V_fixture_max = 3.400
|  time   V(typ)   V(min)   V(max)
0s        3.3V       3.2V       3.4V
387ps     3.3V       3.2V       3.396V
482ps     3.295V     3.2V       3.153V
582ps     3.097V     3.193V     2.88V
668ps     2.913V     3.074V     2.762V
771ps     2.799V     2.914V     2.685V
868ps     2.742V     2.827V     2.646V
1.015ns   2.7V       2.764V     2.614V
1.516ns   2.664V     2.715V     2.587V
50ns      2.644V     2.697V     2.566V
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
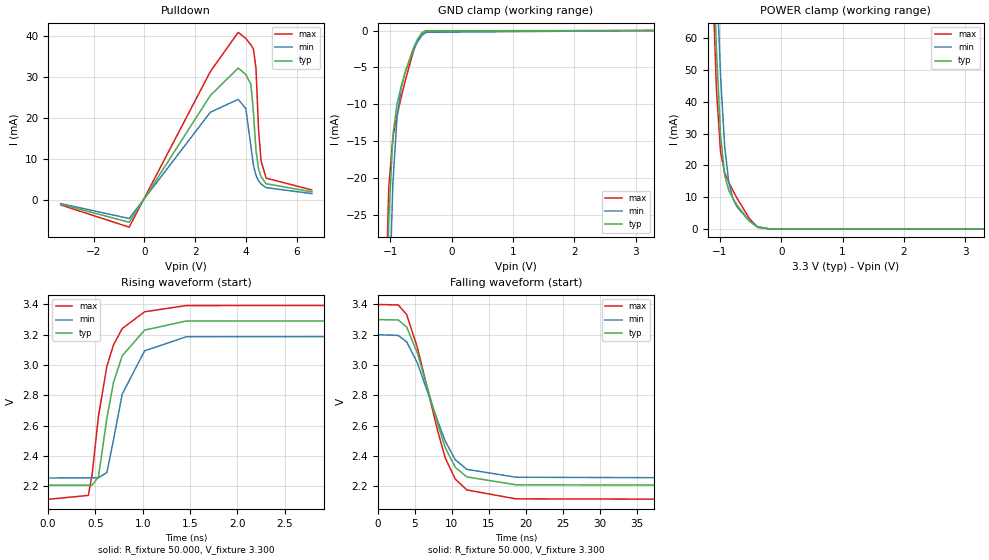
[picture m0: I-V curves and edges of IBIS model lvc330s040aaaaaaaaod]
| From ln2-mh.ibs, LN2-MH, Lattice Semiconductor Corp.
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|   Model lvc330s040aaaaaaaaod
[Model] lvc330s040aaaaaaaaod
Model_type I/O_open_drain
Polarity   Non-Inverting
Enable   Active-Low
Vinl =  0.800V
Vinh =  2.000V
Vmeas =  1.650V
Cref =  0.0F
Rref =  1000
Vref =  3.30V
C_comp   2.000pF   1.500pF   2.500pF
[Temperature Range]   25.000   0.125k   -40.000
[Voltage Range]   3.300V   3.200V   3.400V
[C Comp Corner]
C_comp   2.000pF   1.500pF   2.500pF
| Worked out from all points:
|   slope of the pulldown table from 0 to 0.495 V, typ, clamps not added: 98.5 ohm
|   GND clamp passes 1 mA (typ) near -0.54 V on its own axis
|   POWER clamp passes 1 mA (typ) near -0.43 V on its own axis
|   rising waveform, R_fixture 50.000, V_fixture 3.300: 20-80 % time 224ps typ, 234ps min, 215ps max; typ from 2.21 V to 3.3 V
|   falling waveform, R_fixture 50.000, V_fixture 3.300: 20-80 % time 4.01ns typ, 4.25ns min, 4.02ns max; typ from 3.3 V to 2.21 V
[Pulldown]
|Voltage   I(typ)   I(min)   I(max)
-3.3V     -991.1uA   -858.3uA   -1.183mA
-600mV    -5.406mA   -4.489mA   -6.6mA
2.6V      25.49mA    21.41mA    31.32mA
3.7V      32.19mA    24.56mA    40.89mA
4V        30.59mA    22.3mA     39.39mA
4.2V      28.23mA    13.08mA    37.81mA
4.3V      21.31mA    8.47mA     36.8mA
4.4V      12.1mA     6.034mA    32.08mA
4.5V      7.681mA    4.709mA    17.27mA
4.6V      5.686mA    3.907mA    9.552mA
4.8V      3.997mA    3.033mA    5.35mA
6.6V      2.008mA    1.58mA     2.473mA
[GND_clamp]
|Voltage   I(typ)   I(min)   I(max)
-3.3V     -1.861A    -1.855A    -1.868A
-1.089V   -50.81mA   -68.2mA    -41.77mA
-1.022V   -25.74mA   -39.08mA   -21.31mA
-955mV    -14.26mA   -20.73mA   -14.54mA
-888mV    -9.982mA   -11.84mA   -11.55mA
-821mV    -7.603mA   -7.856mA   -9.113mA
-754mV    -5.655mA   -5.623mA   -6.821mA
-620mV    -2.371mA   -2.616mA   -2.797mA
-553mV    -1.172mA   -1.518mA   -1.313mA
-486mV    -396.2uA   -716.4uA   -376.4uA
-419mV    -71.95uA   -244.9uA   -42.84uA
3.3V      0A         0A         0A
[POWER_clamp]
|Voltage   I(typ)   I(min)   I(max)
-3.266V   2.002A     2.005A     2.003A
-1.122V   95.84mA    122.3mA    80.75mA
-1.055V   56.42mA    81.13mA    43.84mA
-988mV    29.46mA    48.05mA    24.15mA
-921mV    16.84mA    25.99mA    17.71mA
-854mV    12.12mA    14.6mA     14.67mA
-787mV    9.585mA    9.535mA    12.12mA
-720mV    7.529mA    6.931mA    9.676mA
-519mV    2.487mA    2.496mA    3.276mA
-385mV    477.3uA    731.6uA    579.8uA
-184mV    1.009uA    11.15uA    276.7nA
3.3V      0A         0A         0A
[Ramp]
| variable   typ   min   max
dV/dt_r   0.669/4.516n   0.572/4.829n   0.790/4.506n
dV/dt_f   0.670/4.024n   0.580/4.263n   0.788/4.032n
R_load = 50.000
[Rising Waveform]
R_fixture = 50.000
V_fixture = 3.300
V_fixture_min = 3.200
V_fixture_max = 3.400
|  time   V(typ)   V(min)   V(max)
0s        2.206V     2.254V     2.113V
425ps     2.206V     2.255V     2.139V
466ps     2.207V     2.255V     2.282V
532ps     2.262V     2.255V     2.663V
621ps     2.649V     2.29V      2.992V
690ps     2.883V     2.503V     3.132V
783ps     3.061V     2.808V     3.241V
1.02ns    3.231V     3.094V     3.352V
1.46ns    3.291V     3.187V     3.393V
50ns      3.3V       3.2V       3.4V
[Falling Waveform]
R_fixture = 50.000
V_fixture = 3.300
V_fixture_min = 3.200
V_fixture_max = 3.400
|  time   V(typ)   V(min)   V(max)
0s        3.3V       3.2V       3.4V
2.756ns   3.298V     3.196V     3.397V
3.9ns     3.251V     3.153V     3.333V
5.376ns   3.075V     3.01V      3.11V
8.085ns   2.614V     2.631V     2.566V
9.106ns   2.455V     2.498V     2.387V
10.46ns   2.325V     2.375V     2.247V
12.03ns   2.261V     2.311V     2.175V
18.67ns   2.209V     2.259V     2.116V
50ns      2.206V     2.254V     2.113V
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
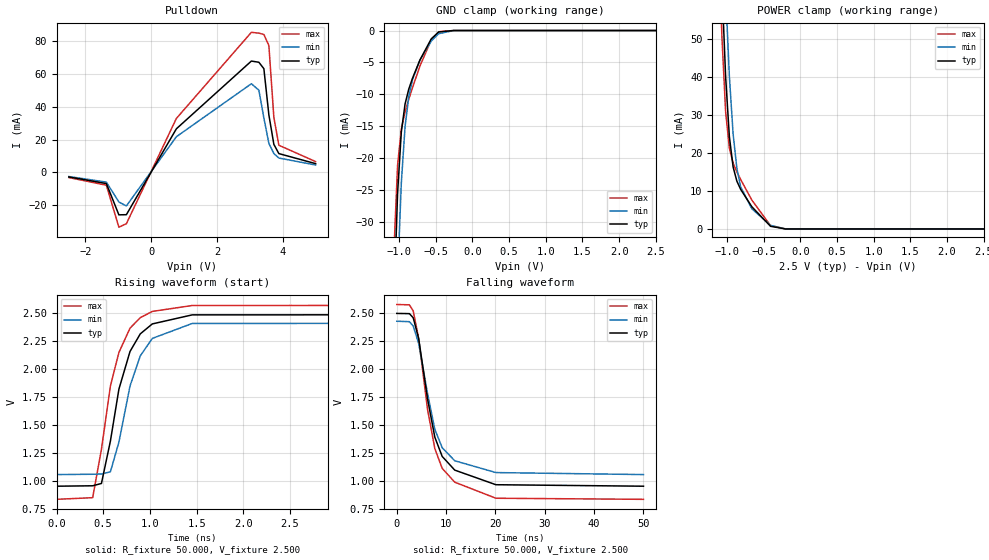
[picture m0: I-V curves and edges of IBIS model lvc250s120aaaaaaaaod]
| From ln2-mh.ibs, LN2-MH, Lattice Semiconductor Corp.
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|   Model lvc250s120aaaaaaaaod
[Model] lvc250s120aaaaaaaaod
Model_type I/O_open_drain
Polarity   Non-Inverting
Enable   Active-Low
Vinl =  0.700V
Vinh =  1.700V
Vmeas =  1.250V
Cref =  0.0F
Rref =  1000
Vref =  2.50V
C_comp   2.000pF   1.500pF   2.500pF
[Temperature Range]   25.000   0.125k   -40.000
[Voltage Range]   2.500V   2.430V   2.580V
[C Comp Corner]
C_comp   2.000pF   1.500pF   2.500pF
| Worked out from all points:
|   slope of the pulldown table from 0 to 0.375 V, typ, clamps not added: 26 ohm
|   GND clamp passes 1 mA (typ) near -0.54 V on its own axis
|   POWER clamp passes 1 mA (typ) near -0.43 V on its own axis
|   rising waveform, R_fixture 50.000, V_fixture 2.500: 20-80 % time 245ps typ, 254ps min, 237ps max; typ from 0.951 V to 2.5 V
|   falling waveform, R_fixture 50.000, V_fixture 2.500: 20-80 % time 3.93ns typ, 3.98ns min, 3.86ns max; typ from 2.5 V to 0.951 V
[Pulldown]
|Voltage   I(typ)   I(min)   I(max)
-2.5V     -2.714mA   -2.454mA   -3.099mA
-1.36V    -6.743mA   -5.871mA   -7.753mA
-980mV    -25.82mA   -17.98mA   -33.34mA
-752mV    -25.74mA   -20.4mA    -31.26mA
768mV     26.64mA    21.81mA    32.95mA
3.048V    67.96mA    54.13mA    85.49mA
3.276V    67.23mA    50.2mA     84.98mA
3.428V    63.31mA    33.27mA    84.18mA
3.58V     35.15mA    17.71mA    77.43mA
3.732V    17.14mA    11.54mA    33.56mA
3.884V    11.52mA    8.821mA    16.63mA
5V        5.406mA    4.566mA    6.645mA
[GND_clamp]
|Voltage   I(typ)   I(min)   I(max)
-2.5V     -1.176A    -1.175A    -1.18A
-1.072V   -43.12mA   -59.87mA   -34.84mA
-1.021V   -25.46mA   -38.72mA   -21.1mA
-970mV    -15.9mA    -23.88mA   -15.42mA
-919mV    -11.5mA    -15.05mA   -12.74mA
-868mV    -9.155mA   -10.31mA   -10.74mA
-817mV    -7.451mA   -7.678mA   -8.924mA
-715mV    -4.588mA   -4.605mA   -5.525mA
-562mV    -1.31mA    -1.648mA   -1.483mA
-460mV    -221.2uA   -492.9uA   -183.3uA
-256mV    -336.9nA   -5.429uA   -53.89nA
2.5V      0A         0A         0A
[POWER_clamp]
|Voltage   I(typ)   I(min)   I(max)
-2.498V   1.294A     1.303A     1.292A
-1.121V   95.13mA    121.6mA    80.05mA
-1.07V    64.31mA    89.69mA    50.73mA
-1.019V   40mA       62.1mA     30.81mA
-968mV    24.27mA    40.19mA    21.27mA
-917mV    16.31mA    24.99mA    17.34mA
-866mV    12.6mA     15.97mA    15.03mA
-815mV    10.45mA    11.12mA    13.06mA
-662mV    5.856mA    5.328mA    7.611mA
-407mV    698.4uA    949.4uA    879.7uA
-203mV    1.851uA    18.03uA    575.7nA
2.5V      0A         0A         0A
[Ramp]
| variable   typ   min   max
dV/dt_r   0.959/3.806n   0.842/3.982n   1.086/3.676n
dV/dt_f   0.952/3.924n   0.845/3.978n   1.072/3.860n
R_load = 50.000
[Rising Waveform]
R_fixture = 50.000
V_fixture = 2.500
V_fixture_min = 2.430
V_fixture_max = 2.580
|  time   V(typ)   V(min)   V(max)
0s        950.8mV    1.055V     833.1mV
387ps     954.5mV    1.058V     847.9mV
481ps     975.5mV    1.06V      1.282V
577ps     1.356V     1.08V      1.849V
668ps     1.821V     1.346V     2.15V
787ps     2.159V     1.85V      2.368V
897ps     2.317V     2.12V      2.462V
1.026ns   2.406V     2.276V     2.518V
1.453ns   2.487V     2.41V      2.571V
50ns      2.5V       2.43V      2.58V
[Falling Waveform]
R_fixture = 50.000
V_fixture = 2.500
V_fixture_min = 2.430
V_fixture_max = 2.580
|  time   V(typ)   V(min)   V(max)
0s        2.5V       2.43V      2.58V
2.556ns   2.498V     2.426V     2.577V
3.33ns    2.461V     2.387V     2.523V
4.426ns   2.277V     2.233V     2.277V
6.236ns   1.733V     1.782V     1.639V
7.706ns   1.391V     1.461V     1.289V
9.2ns     1.218V     1.296V     1.111V
11.75ns   1.095V     1.179V     986.8mV
20.09ns   964.1mV    1.073V     842.8mV
50ns      950.8mV    1.055V     833.1mV
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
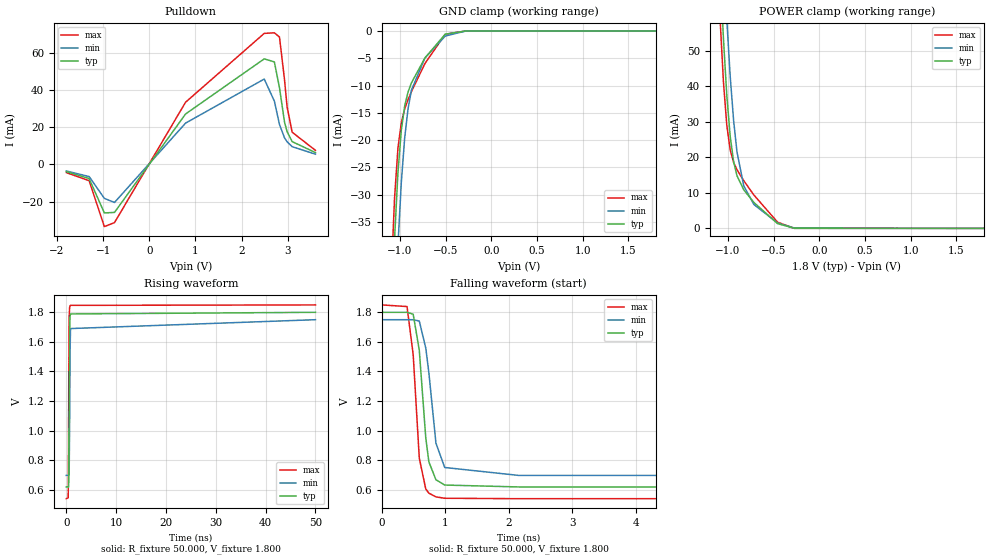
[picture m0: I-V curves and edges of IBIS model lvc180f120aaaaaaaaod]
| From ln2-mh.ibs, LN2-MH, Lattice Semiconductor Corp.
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|   Model lvc180f120aaaaaaaaod
[Model] lvc180f120aaaaaaaaod
Model_type I/O_open_drain
Polarity   Non-Inverting
Enable   Active-Low
Vinl =  0.630V
Vinh =  1.170V
Vmeas =  0.900V
Cref =  0.0F
Rref =  1000
Vref =  1.80V
C_comp   2.000pF   1.500pF   2.500pF
[Temperature Range]   25.000   0.125k   -40.000
[Voltage Range]   1.800V   1.750V   1.850V
[C Comp Corner]
C_comp   2.000pF   1.500pF   2.500pF
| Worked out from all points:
|   slope of the pulldown table from 0 to 0.27 V, typ, clamps not added: 25.5 ohm
|   GND clamp passes 1 mA (typ) near -0.54 V on its own axis
|   POWER clamp passes 1 mA (typ) near -0.43 V on its own axis
|   rising waveform, R_fixture 50.000, V_fixture 1.800: 20-80 % time 105ps typ, 127ps min, 88.2ps max; typ from 0.618 V to 1.8 V
|   falling waveform, R_fixture 50.000, V_fixture 1.800: 20-80 % time 132ps typ, 156ps min, 114ps max; typ from 1.8 V to 0.618 V
[Pulldown]
|Voltage   I(typ)   I(min)   I(max)
-1.8V     -3.877mA   -3.515mA   -4.389mA
-1.305V   -7.584mA   -6.516mA   -8.753mA
-975mV    -26.06mA   -18.23mA   -33.39mA
-755mV    -25.77mA   -20.44mA   -31.26mA
785mV     27.08mA    22.18mA    33.4mA
2.49V     56.7mA     45.85mA    70.38mA
2.71V     55.03mA    33.97mA    70.68mA
2.82V     41.23mA    21.46mA    68.45mA
2.93V     22.68mA    14.26mA    45.39mA
2.985V    17.62mA    12.18mA    30.98mA
3.095V    12.25mA    9.529mA    17.31mA
3.6V      6.356mA    5.498mA    7.532mA
[GND_clamp]
|Voltage   I(typ)   I(min)   I(max)
-1.8V     -585.7mA   -591.6mA   -585.2mA
-1.097V   -54.7mA    -72.3mA    -45.44mA
-1.06V    -38.22mA   -54.4mA    -30.73mA
-1.023V   -26.04mA   -39.44mA   -21.56mA
-986mV    -18.22mA   -27.85mA   -16.81mA
-949mV    -13.75mA   -19.63mA   -14.29mA
-912mV    -11.19mA   -14.24mA   -12.58mA
-875mV    -9.506mA   -10.84mA   -11.12mA
-727mV    -4.941mA   -4.928mA   -5.958mA
-505mV    -576.1uA   -916.7uA   -589.6uA
-283mV    -824.2nA   -10.84uA   -168.9nA
1.8V      0A         0A         0A
[POWER_clamp]
|Voltage   I(typ)   I(min)   I(max)
-1.789V   650.9mA    666.7mA    643.9mA
-1.086V   73.37mA    99.35mA    59.09mA
-1.049V   53.37mA    77.75mA    41.19mA
-1.012V   37.31mA    58.71mA    28.94mA
-975mV    25.9mA     42.77mA    22.1mA
-938mV    18.85mA    30.42mA    18.6mA
-901mV    14.84mA    21.56mA    16.51mA
-827mV    10.86mA    11.99mA    13.46mA
-716mV    7.305mA    6.728mA    9.397mA
-457mV    1.344mA    1.526mA    1.755mA
-272mV    20.87uA    98.79uA    12.36uA
1.8V      0A         0A         0A
[Ramp]
| variable   typ   min   max
dV/dt_r   0.711/0.140n   0.627/0.169n   0.794/0.116n
dV/dt_f   0.709/0.132n   0.632/0.156n   0.787/0.114n
R_load = 50.000
[Rising Waveform]
R_fixture= 50.000
V_fixture= 1.800
V_fixture_min= 1.750
V_fixture_max= 1.850
|time   V(typ)   V(min)   V(max)
0s        618mV      696mV      538.5mV
388ps     619.6mV    696.8mV    544.9mV
451ps     616.9mV    697.4mV    915.9mV
489ps     650.5mV    697.5mV    1.283V
527ps     835.5mV    696.2mV    1.616V
577ps     1.146V     709.6mV    1.772V
670ps     1.68V      1.052V     1.833V
755ps     1.771V     1.51V      1.843V
842ps     1.789V     1.69V      1.847V
50ns      1.8V       1.75V      1.85V
[Falling Waveform]
R_fixture= 50.000
V_fixture= 1.800
V_fixture_min= 1.750
V_fixture_max= 1.850
|time   V(typ)   V(min)   V(max)
0s        1.8V       1.75V      1.85V
398ps     1.8V       1.75V      1.839V
495ps     1.787V     1.75V      1.513V
591ps     1.543V     1.741V     812.8mV
693ps     949.9mV    1.558V     604.1mV
742ps     787.6mV    1.39V      576.1mV
853ps     666.8mV    914.2mV    550.6mV
991ps     630.9mV    749.7mV    541.4mV
2.157ns   618mV      696mV      538.5mV
50ns      618mV      695.9mV    538.5mV
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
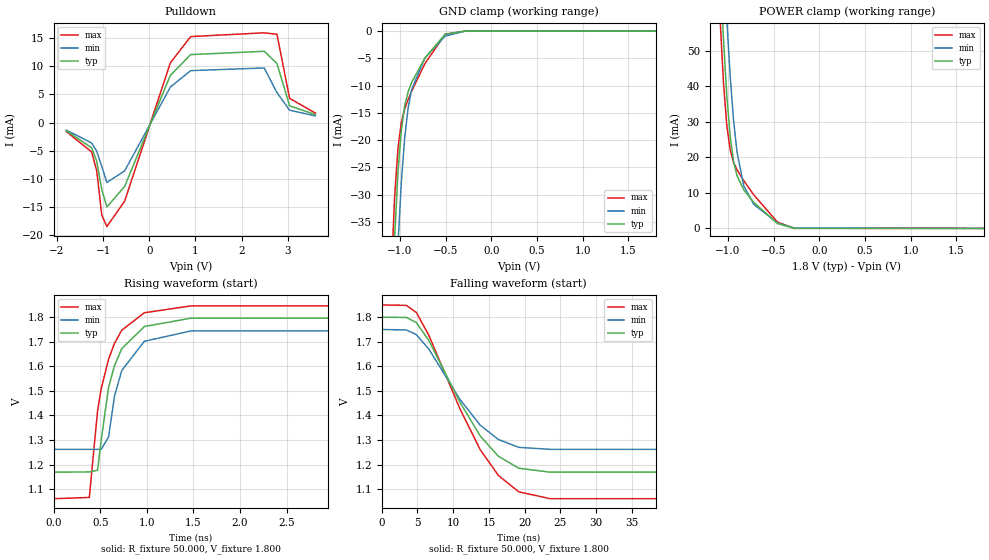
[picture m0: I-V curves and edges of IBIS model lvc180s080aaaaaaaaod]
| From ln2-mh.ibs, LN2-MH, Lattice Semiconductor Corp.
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|   Model lvc180s080aaaaaaaaod
[Model] lvc180s080aaaaaaaaod
Model_type I/O_open_drain
Polarity   Non-Inverting
Enable   Active-Low
Vinl =  0.630V
Vinh =  1.170V
Vmeas =  0.900V
Cref =  0.0F
Rref =  1000
Vref =  1.80V
C_comp   2.000pF   1.500pF   2.500pF
[Temperature Range]   25.000   0.125k   -40.000
[Voltage Range]   1.800V   1.750V   1.850V
[C Comp Corner]
C_comp   2.000pF   1.500pF   2.500pF
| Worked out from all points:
|   slope of the pulldown table from 0 to 0.27 V, typ, clamps not added: 50.5 ohm
|   GND clamp passes 1 mA (typ) near -0.54 V on its own axis
|   POWER clamp passes 1 mA (typ) near -0.43 V on its own axis
|   rising waveform, R_fixture 50.000, V_fixture 1.800: 20-80 % time 225ps typ, 224ps min, 230ps max; typ from 1.17 V to 1.8 V
|   falling waveform, R_fixture 50.000, V_fixture 1.800: 20-80 % time 7.15ns typ, 6.8ns min, 7.56ns max; typ from 1.8 V to 1.17 V
[Pulldown]
|Voltage   I(typ)   I(min)   I(max)
-1.8V     -1.467mA   -1.347mA   -1.594mA
-1.25V    -4.497mA   -3.644mA   -5.247mA
-1.14V    -6.904mA   -5.119mA   -8.606mA
-1.03V    -11.99mA   -7.86mA    -16.51mA
-920mV    -15.03mA   -10.67mA   -18.53mA
-535mV    -11.38mA   -8.605mA   -14mA
455mV     8.405mA    6.311mA    10.62mA
895mV     12.1mA     9.244mA    15.31mA
2.49V     12.69mA    9.718mA    15.98mA
2.765V    10.53mA    5.338mA    15.72mA
3.04V     2.979mA    2.201mA    4.31mA
3.6V      1.405mA    1.18mA     1.674mA
[GND_clamp]
|Voltage   I(typ)   I(min)   I(max)
-1.8V     -585.7mA   -591.6mA   -585.2mA
-1.097V   -54.7mA    -72.3mA    -45.44mA
-1.06V    -38.22mA   -54.4mA    -30.73mA
-1.023V   -26.04mA   -39.44mA   -21.56mA
-986mV    -18.22mA   -27.85mA   -16.81mA
-949mV    -13.75mA   -19.63mA   -14.29mA
-912mV    -11.19mA   -14.24mA   -12.58mA
-875mV    -9.506mA   -10.84mA   -11.12mA
-727mV    -4.941mA   -4.928mA   -5.958mA
-505mV    -576.1uA   -916.7uA   -589.6uA
-283mV    -824.2nA   -10.84uA   -168.9nA
1.8V      0A         0A         0A
[POWER_clamp]
|Voltage   I(typ)   I(min)   I(max)
-1.789V   650.9mA    666.7mA    643.9mA
-1.086V   73.37mA    99.35mA    59.09mA
-1.049V   53.37mA    77.75mA    41.19mA
-1.012V   37.31mA    58.71mA    28.94mA
-975mV    25.9mA     42.77mA    22.1mA
-938mV    18.85mA    30.42mA    18.6mA
-901mV    14.84mA    21.56mA    16.51mA
-827mV    10.86mA    11.99mA    13.46mA
-716mV    7.305mA    6.728mA    9.397mA
-457mV    1.344mA    1.526mA    1.755mA
-272mV    20.87uA    98.79uA    12.36uA
1.8V      0A         0A         0A
[Ramp]
| variable   typ   min   max
dV/dt_r   0.379/7.233n   0.306/6.985n   0.474/7.653n
dV/dt_f   0.386/7.149n   0.299/6.802n   0.483/7.598n
R_load = 50.000
[Rising Waveform]
R_fixture = 50.000
V_fixture = 1.800
V_fixture_min = 1.750
V_fixture_max = 1.850
|  time   V(typ)   V(min)   V(max)
0s        1.169V     1.262V     1.061V
381ps     1.17V      1.262V     1.066V
470ps     1.177V     1.262V     1.419V
509ps     1.3V       1.262V     1.509V
588ps     1.515V     1.312V     1.629V
652ps     1.603V     1.479V     1.694V
730ps     1.672V     1.583V     1.747V
972ps     1.762V     1.702V     1.818V
1.472ns   1.796V     1.744V     1.846V
50ns      1.8V       1.75V      1.85V
[Falling Waveform]
R_fixture = 50.000
V_fixture = 1.800
V_fixture_min = 1.750
V_fixture_max = 1.850
|  time   V(typ)   V(min)   V(max)
0s        1.8V       1.75V      1.85V
3.455ns   1.799V     1.748V     1.848V
4.845ns   1.778V     1.729V     1.819V
6.595ns   1.705V     1.67V      1.726V
10.96ns   1.453V     1.465V     1.426V
13.79ns   1.316V     1.36V      1.26V
16.32ns   1.234V     1.302V     1.156V
19.18ns   1.185V     1.27V      1.089V
23.58ns   1.169V     1.262V     1.061V
50ns      1.169V     1.262V     1.061V
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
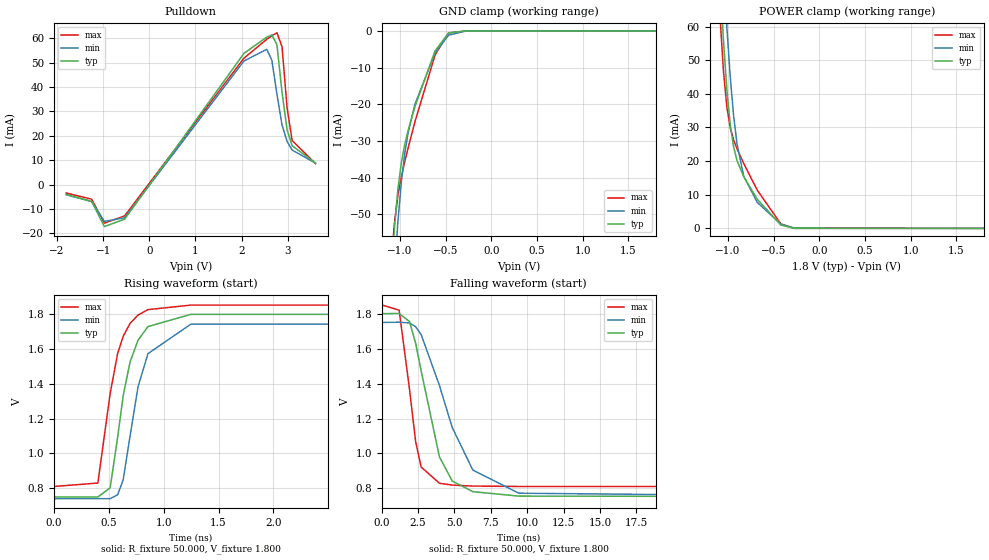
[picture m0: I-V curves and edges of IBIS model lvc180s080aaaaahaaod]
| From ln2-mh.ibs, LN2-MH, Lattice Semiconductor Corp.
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|   Model lvc180s080aaaaahaaod
[Model] lvc180s080aaaaahaaod
Model_type I/O_open_drain
Polarity   Non-Inverting
Enable   Active-Low
Vinl =  0.630V
Vinh =  1.170V
Vmeas =  0.900V
Cref =  0.0F
Rref =  1000
Vref =  1.80V
C_comp   2.000pF   1.500pF   2.500pF
[Temperature Range]   25.000   0.125k   -40.000
[Voltage Range]   1.800V   1.750V   1.850V
[C Comp Corner]
C_comp   2.000pF   1.500pF   2.500pF
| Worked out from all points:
|   slope of the pulldown table from 0 to 0.27 V, typ, clamps not added: 35.6 ohm
|   GND clamp passes 1 mA (typ) near -0.49 V on its own axis
|   POWER clamp passes 1 mA (typ) near -0.42 V on its own axis
|   rising waveform, R_fixture 50.000, V_fixture 1.800: 20-80 % time 172ps typ, 184ps min, 166ps max; typ from 0.752 V to 1.8 V
|   falling waveform, R_fixture 50.000, V_fixture 1.800: 20-80 % time 1.61ns typ, 2.59ns min, 882ps max; typ from 1.8 V to 0.752 V
[Pulldown]
|Voltage   I(typ)   I(min)   I(max)
-1.8V     -3.995mA   -4.156mA   -3.426mA
-1.25V    -6.87mA    -6.937mA   -5.952mA
-975mV    -17.19mA   -15.06mA   -15.77mA
-535mV    -14.15mA   -13.58mA   -12.81mA
2.05V     53.77mA    50.66mA    51.81mA
2.545V    60.45mA    55.46mA    59.56mA
2.655V    61.33mA    51mA       61.01mA
2.765V    57.36mA    37.1mA     62.21mA
2.875V    37.94mA    24.45mA    56.6mA
2.985V    22.51mA    17.73mA    31.43mA
3.095V    15.94mA    14.16mA    18.1mA
3.6V      8.884mA    8.817mA    8.598mA
[GND_clamp]
|Voltage   I(typ)   I(min)   I(max)
-1.8V     -570.9mA   -571.8mA   -572.9mA
-1.097V   -67.54mA   -81.64mA   -63.35mA
-1.06V    -53.45mA   -65.42mA   -52.13mA
-1.023V   -43.13mA   -51.95mA   -44.86mA
-986mV    -36.04mA   -41.41mA   -39.83mA
-949mV    -31.06mA   -33.56mA   -35.72mA
-912mV    -27.18mA   -27.83mA   -31.97mA
-838mV    -20.73mA   -20.06mA   -24.86mA
-616mV    -5.403mA   -5.958mA   -6.517mA
-468mV    -530.3uA   -1.122mA   -495.6uA
-283mV    -1.808uA   -19.61uA   -457.7nA
1.8V      0A         0A         0A
[POWER_clamp]
|Voltage   I(typ)   I(min)   I(max)
-1.789V   617.6mA    624.8mA    616.1mA
-1.086V   74.43mA    97.5mA     62.76mA
-1.049V   55.98mA    77.5mA     46.8mA
-1.012V   41.32mA    59.89mA    36.12mA
-975mV    30.91mA    45.13mA    29.96mA
-938mV    24.29mA    33.57mA    26.33mA
-901mV    20.21mA    25.16mA    23.7mA
-827mV    15.35mA    15.5mA     19.29mA
-679mV    8.657mA    7.724mA    11.36mA
-420mV    977.9uA    1.256mA    1.313mA
-272mV    22.92uA    106.7uA    14.08uA
1.8V      0A         0A         0A
[Ramp]
| variable   typ   min   max
dV/dt_r   0.614/2.366n   0.586/3.556n   0.615/1.446n
dV/dt_f   0.629/1.616n   0.605/2.592n   0.623/0.884n
R_load = 50.000
[Rising Waveform]
R_fixture= 50.000
V_fixture= 1.800
V_fixture_min= 1.750
V_fixture_max= 1.850
|time   V(typ)   V(min)   V(max)
0s        751.5mV    741.2mV    811.1mV
401ps     751mV      741.3mV    830.7mV
513ps     803.6mV    741.4mV    1.343V
581ps     1.092V     763.7mV    1.572V
632ps     1.332V     849.8mV    1.671V
694ps     1.523V     1.099V     1.744V
767ps     1.648V     1.382V     1.792V
857ps     1.726V     1.571V     1.823V
1.248ns   1.796V     1.74V      1.849V
50ns      1.8V       1.75V      1.85V
[Falling Waveform]
R_fixture= 50.000
V_fixture= 1.800
V_fixture_min= 1.750
V_fixture_max= 1.850
|time   V(typ)   V(min)   V(max)
0s        1.8V       1.75V      1.85V
1.196ns   1.801V     1.751V     1.82V
1.906ns   1.755V     1.747V     1.369V
2.332ns   1.63V      1.725V     1.067V
2.711ns   1.472V     1.68V      922.4mV
3.966ns   980.6mV    1.389V     829.6mV
4.845ns   842.3mV    1.149V     819.1mV
6.261ns   781.5mV    905.2mV    813.4mV
9.421ns   756mV      772.6mV    811.3mV
50ns      751.5mV    741.2mV    811.1mV
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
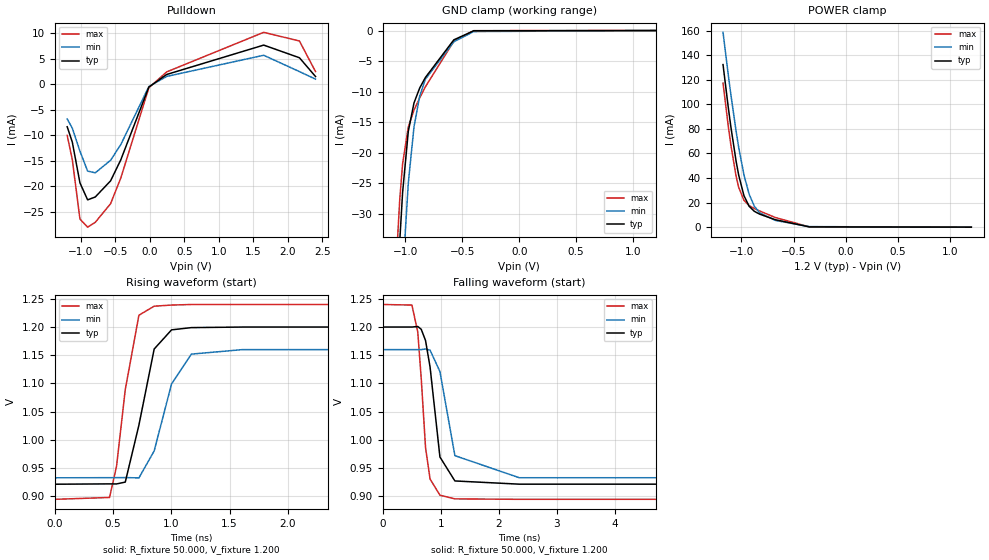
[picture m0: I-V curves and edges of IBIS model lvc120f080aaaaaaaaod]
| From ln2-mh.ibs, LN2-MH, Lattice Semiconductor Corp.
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|   Model lvc120f080aaaaaaaaod
[Model] lvc120f080aaaaaaaaod
Model_type I/O_open_drain
Polarity   Non-Inverting
Enable   Active-Low
Vinl =  0.420V
Vinh =  0.780V
Vmeas =  0.600V
Cref =  0.0F
Rref =  1000
Vref =  1.20V
C_comp   2.000pF   1.500pF   2.500pF
[Temperature Range]   25.000   0.125k   -40.000
[Voltage Range]   1.200V   1.160V   1.240V
[C Comp Corner]
C_comp   2.000pF   1.500pF   2.500pF
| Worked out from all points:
|   slope of the pulldown table from 0 to 0.18 V, typ, clamps not added: 106 ohm
|   GND clamp passes 1 mA (typ) near -0.54 V on its own axis
|   POWER clamp passes 1 mA (typ) near -0.43 V on its own axis
|   rising waveform, R_fixture 50.000, V_fixture 1.200: 20-80 % time 148ps typ, 179ps min, 118ps max; typ from 0.921 V to 1.2 V
|   falling waveform, R_fixture 50.000, V_fixture 1.200: 20-80 % time 172ps typ, 226ps min, 136ps max; typ from 1.2 V to 0.921 V
[Pulldown]
|Voltage   I(typ)   I(min)   I(max)
-1.2V     -8.325mA   -6.797mA   -10.02mA
-1.126V   -11.33mA   -8.597mA   -14.76mA
-1.015V   -19.34mA   -13.12mA   -26.44mA
-904mV    -22.67mA   -17.02mA   -28.03mA
-793mV    -22.11mA   -17.37mA   -27.08mA
-571mV    -18.94mA   -14.9mA    -23.43mA
-423mV    -14.82mA   -11.83mA   -18.39mA
-16mV     -533.1uA   -428.3uA   -667.4uA
243mV     1.939mA    1.556mA    2.448mA
1.649V    7.704mA    5.708mA    10.21mA
2.167V    5.219mA    2.502mA    8.508mA
2.4V      1.54mA     1.023mA    2.507mA
[GND_clamp]
|Voltage   I(typ)   I(min)   I(max)
-1.2V     -115.8mA   -133.1mA   -106.7mA
-1.1V     -56.13mA   -73.78mA   -46.76mA
-1.075V   -44.35mA   -61.25mA   -35.92mA
-1.05V    -34.39mA   -49.96mA   -27.58mA
-1.025V   -26.47mA   -40.07mA   -21.79mA
-975mV    -16.49mA   -24.96mA   -15.78mA
-925mV    -11.84mA   -15.75mA   -13.01mA
-875mV    -9.407mA   -10.74mA   -11.02mA
-825mV    -7.688mA   -7.964mA   -9.21mA
-575mV    -1.526mA   -1.839mA   -1.756mA
-400mV    -41.92uA   -170.5uA   -22.66uA
1.2V      2.666pA    5.169nA    0A
[POWER_clamp]
|Voltage   I(typ)   I(min)   I(max)
-1.175V   132.4mA    158.7mA    117.3mA
-1.125V   97.66mA    124.2mA    82.52mA
-1.1V     81.7mA     108mA      66.94mA
-1.05V    53.7mA     78.16mA    41.43mA
-1.025V   42.27mA    64.92mA    32.37mA
-975mV    25.7mA     42.62mA    21.86mA
-925mV    16.96mA    26.72mA    17.53mA
-875mV    12.88mA    16.98mA    15.14mA
-825mV    10.61mA    11.65mA    13.19mA
-675mV    6.055mA    5.5mA      7.862mA
-350mV    219.1uA    435.6uA    237.4uA
1.2V      0A         0A         0A
[Ramp]
| variable   typ   min   max
dV/dt_r   0.167/0.196n   0.136/0.252n   0.207/0.157n
dV/dt_f   0.167/0.173n   0.136/0.227n   0.207/0.136n
R_load = 50.000
[Rising Waveform]
R_fixture = 50.000
V_fixture = 1.200
V_fixture_min = 1.160
V_fixture_max = 1.240
|  time   V(typ)   V(min)   V(max)
0s        921.2mV    932.6mV    894.4mV
470ps     921.8mV    932.8mV    897.7mV
530ps     921.7mV    932.9mV    952.9mV
605ps     925mV      933mV      1.089V
722ps     1.026V     932.4mV    1.221V
853ps     1.161V     980.3mV    1.237V
1.002ns   1.195V     1.099V     1.239V
1.172ns   1.199V     1.152V     1.24V
1.613ns   1.2V       1.16V      1.24V
50ns      1.2V       1.16V      1.24V
[Falling Waveform]
R_fixture = 50.000
V_fixture = 1.200
V_fixture_min = 1.160
V_fixture_max = 1.240
|  time   V(typ)   V(min)   V(max)
0s        1.2V       1.16V      1.24V
504ps     1.2V       1.16V      1.239V
605ps     1.201V     1.16V      1.191V
665ps     1.196V     1.16V      1.108V
739ps     1.176V     1.161V     985.9mV
817ps     1.129V     1.159V     930.4mV
987ps     969.5mV    1.121V     901.7mV
1.245ns   927mV      971.9mV    895.2mV
2.355ns   921.3mV    932.7mV    894.4mV
50ns      921.2mV    932.6mV    894.4mV
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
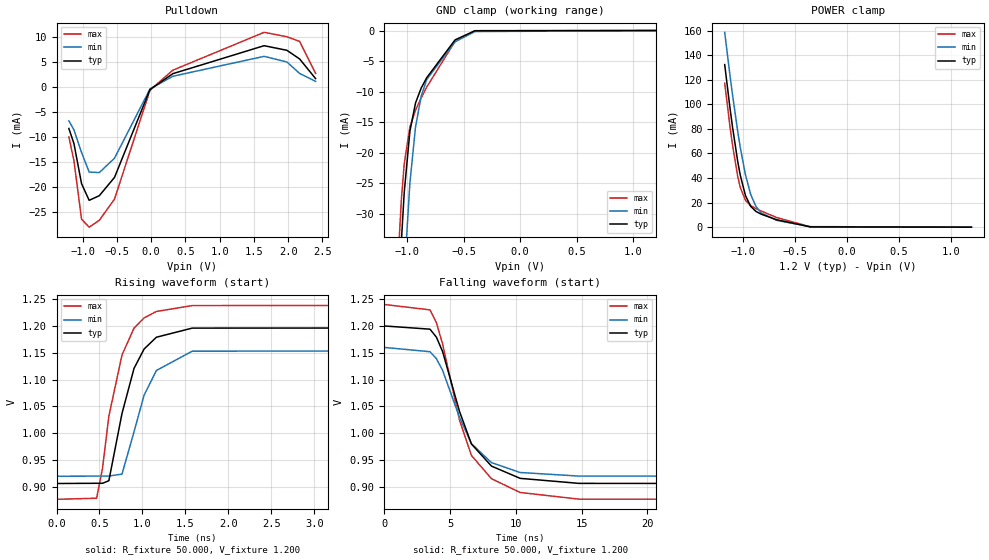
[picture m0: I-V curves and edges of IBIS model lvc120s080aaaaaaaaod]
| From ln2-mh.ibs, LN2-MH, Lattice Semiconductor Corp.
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|   Model lvc120s080aaaaaaaaod
[Model] lvc120s080aaaaaaaaod
Model_type I/O_open_drain
Polarity   Non-Inverting
Enable   Active-Low
Vinl =  0.420V
Vinh =  0.780V
Vmeas =  0.600V
Cref =  0.0F
Rref =  1000
Vref =  1.20V
C_comp   2.000pF   1.500pF   2.500pF
[Temperature Range]   25.000   0.125k   -40.000
[Voltage Range]   1.200V   1.160V   1.240V
[C Comp Corner]
C_comp   2.000pF   1.500pF   2.500pF
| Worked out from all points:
|   slope of the pulldown table from 0 to 0.18 V, typ, clamps not added: 101 ohm
|   GND clamp passes 1 mA (typ) near -0.54 V on its own axis
|   POWER clamp passes 1 mA (typ) near -0.43 V on its own axis
|   rising waveform, R_fixture 50.000, V_fixture 1.200: 20-80 % time 270ps typ, 284ps min, 262ps max; typ from 0.906 V to 1.2 V
|   falling waveform, R_fixture 50.000, V_fixture 1.200: 20-80 % time 2.41ns typ, 2.48ns min, 2.41ns max; typ from 1.2 V to 0.906 V
[Pulldown]
|Voltage   I(typ)   I(min)   I(max)
-1.2V     -8.325mA   -6.797mA   -10.02mA
-1.126V   -11.33mA   -8.597mA   -14.76mA
-1.015V   -19.34mA   -13.12mA   -26.44mA
-904mV    -22.67mA   -17.02mA   -28.03mA
-756mV    -21.75mA   -17.13mA   -26.66mA
-534mV    -18.1mA    -14.26mA   -22.43mA
-16mV     -533.1uA   -428.3uA   -667.4uA
317mV     2.619mA    2.103mA    3.315mA
1.649V    8.21mA     6.083mA    10.88mA
1.982V    7.286mA    4.954mA    9.991mA
2.167V    5.561mA    2.667mA    9.067mA
2.4V      1.641mA    1.09mA     2.672mA
[GND_clamp]
|Voltage   I(typ)   I(min)   I(max)
-1.2V     -115.8mA   -133.1mA   -106.7mA
-1.1V     -56.13mA   -73.78mA   -46.76mA
-1.075V   -44.35mA   -61.25mA   -35.92mA
-1.05V    -34.39mA   -49.96mA   -27.58mA
-1.025V   -26.47mA   -40.07mA   -21.79mA
-975mV    -16.49mA   -24.96mA   -15.78mA
-925mV    -11.84mA   -15.75mA   -13.01mA
-875mV    -9.407mA   -10.74mA   -11.02mA
-825mV    -7.688mA   -7.964mA   -9.21mA
-575mV    -1.526mA   -1.839mA   -1.756mA
-400mV    -41.92uA   -170.5uA   -22.66uA
1.2V      2.678pA    5.169nA    0A
[POWER_clamp]
|Voltage   I(typ)   I(min)   I(max)
-1.175V   132.4mA    158.7mA    117.3mA
-1.125V   97.66mA    124.2mA    82.52mA
-1.1V     81.7mA     108mA      66.94mA
-1.05V    53.7mA     78.16mA    41.43mA
-1.025V   42.27mA    64.92mA    32.37mA
-975mV    25.7mA     42.62mA    21.86mA
-925mV    16.96mA    26.72mA    17.53mA
-875mV    12.88mA    16.98mA    15.14mA
-825mV    10.61mA    11.65mA    13.19mA
-675mV    6.055mA    5.5mA      7.862mA
-350mV    219.1uA    435.6uA    237.4uA
1.2V      0A         0A         0A
[Ramp]
| variable   typ   min   max
dV/dt_r   0.176/2.327n   0.144/2.494n   0.218/2.267n
dV/dt_f   0.176/2.408n   0.144/2.504n   0.218/2.411n
R_load = 50.000
[Rising Waveform]
R_fixture = 50.000
V_fixture = 1.200
V_fixture_min = 1.160
V_fixture_max = 1.240
|  time   V(typ)   V(min)   V(max)
0s        906.4mV    919.9mV    876.9mV
467ps     906.8mV    920.2mV    879mV
536ps     906.8mV    920.2mV    935.7mV
609ps     911.6mV    920.3mV    1.032V
762ps     1.037V     923.9mV    1.146V
902ps     1.121V     1.003V     1.196V
1.019ns   1.157V     1.071V     1.215V
1.162ns   1.179V     1.117V     1.227V
1.579ns   1.196V     1.153V     1.238V
50ns      1.2V       1.16V      1.24V
[Falling Waveform]
R_fixture = 50.000
V_fixture = 1.200
V_fixture_min = 1.160
V_fixture_max = 1.240
|  time   V(typ)   V(min)   V(max)
0s        1.2V       1.16V      1.24V
3.464ns   1.194V     1.152V     1.23V
3.954ns   1.179V     1.139V     1.206V
4.427ns   1.152V     1.117V     1.166V
5.705ns   1.041V     1.03V      1.025V
6.614ns   980.1mV    980.7mV    958.7mV
8.142ns   938.8mV    945.3mV    915.3mV
10.32ns   916mV      926.9mV    889.7mV
14.81ns   906.6mV    920.2mV    877.2mV
50ns      906.4mV    919.9mV    876.9mV
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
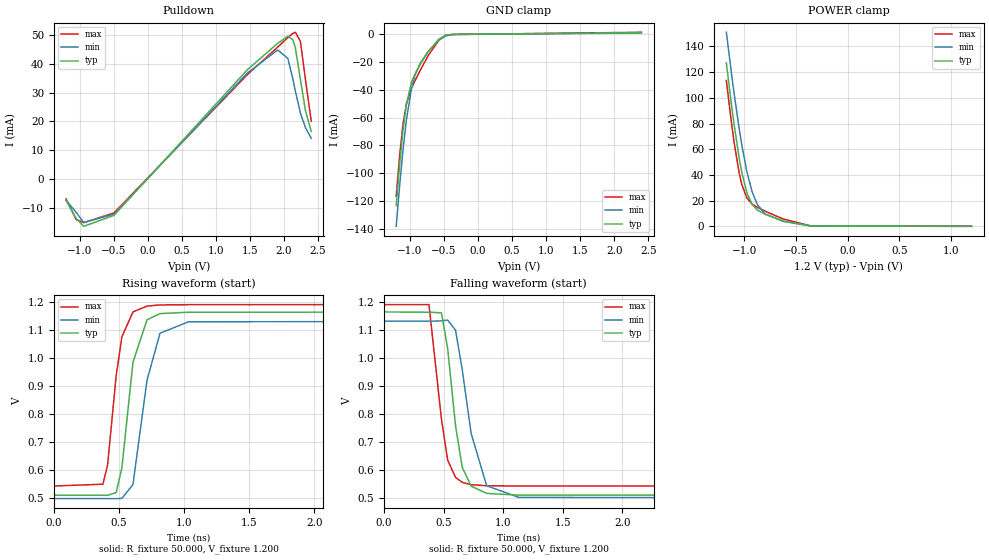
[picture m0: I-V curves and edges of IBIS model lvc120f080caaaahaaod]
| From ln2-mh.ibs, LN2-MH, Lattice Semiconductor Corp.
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|   Model lvc120f080caaaahaaod
[Model] lvc120f080caaaahaaod
Model_type I/O_open_drain
Polarity   Non-Inverting
Enable   Active-Low
Vinl =  0.420V
Vinh =  0.780V
Vmeas =  0.600V
Cref =  0.0F
Rref =  100
Vref =  1.20V
C_comp   2.000pF   1.500pF   2.500pF
[Temperature Range]   25.000   0.125k   -40.000
[Voltage Range]   1.200V   1.160V   1.240V
[C Comp Corner]
C_comp   2.000pF   1.500pF   2.500pF
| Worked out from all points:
|   slope of the pulldown table from 0 to 0.18 V, typ, clamps not added: 38.3 ohm
|   GND clamp passes 1 mA (typ) near -0.47 V on its own axis
|   POWER clamp passes 1 mA (typ) near -0.46 V on its own axis
|   rising waveform, R_fixture 50.000, V_fixture 1.200: 20-80 % time 94.4ps typ, 111ps min, 92ps max; typ from 0.51 V to 1.16 V
|   falling waveform, R_fixture 50.000, V_fixture 1.200: 20-80 % time 106ps typ, 140ps min, 93.6ps max; typ from 1.16 V to 0.51 V
[Pulldown]
|Voltage   I(typ)   I(min)   I(max)
-1.2V     -7.419mA   -7.327mA   -6.854mA
-1.052V   -13.57mA   -11.52mA   -13.99mA
-941mV    -16.34mA   -14.99mA   -15.09mA
-497mV    -12.55mA   -12.17mA   -11.71mA
1.464V    37.98mA    36.83mA    36.29mA
1.908V    47.11mA    44.8mA     45.8mA
2.056V    49.53mA    41.86mA    49.06mA
2.13V     48.33mA    34.77mA    50.55mA
2.167V    45.51mA    30.47mA    50.92mA
2.241V    34.59mA    22.92mA    47.79mA
2.315V    23.77mA    17.84mA    34.5mA
2.4V      16.53mA    14.18mA    20.13mA
[GND_clamp]
|Voltage   I(typ)   I(min)   I(max)
-1.2V     -123mA     -137.9mA   -116.3mA
-1.15V    -93.77mA   -109mA     -87.45mA
-1.1V     -69.04mA   -83.2mA    -64.7mA
-1.05V    -50.52mA   -61.66mA   -50.16mA
-975mV    -34.68mA   -39.02mA   -38.92mA
-925mV    -28.78mA   -29.88mA   -33.66mA
-850mV    -22.06mA   -21.38mA   -26.4mA
-725mV    -12.54mA   -12.25mA   -15.19mA
-575mV    -3.931mA   -4.562mA   -4.668mA
-475mV    -1.083mA   -1.617mA   -1.164mA
-375mV    -415.4uA   -497uA     -482.7uA
2.4V      768.5uA    596.7uA    1.09mA
[POWER_clamp]
|Voltage   I(typ)   I(min)   I(max)
-1.175V   127.2mA    151mA      113.4mA
-1.125V   94.42mA    118.8mA    80.34mA
-1.1V     79.34mA    103.6mA    65.54mA
-1.05V    52.82mA    75.75mA    41.2mA
-1.025V   41.91mA    63.3mA     32.44mA
-975mV    25.85mA    42.18mA    21.92mA
-925mV    17.02mA    26.81mA    17.31mA
-875mV    12.68mA    17.07mA    14.77mA
-800mV    9.315mA    9.719mA    11.8mA
-625mV    4.252mA    3.803mA    5.726mA
-350mV    125.8uA    261.6uA    148.8uA
1.2V      0A         0A         0A
[Ramp]
| variable   typ   min   max
dV/dt_r   0.410/0.119n   0.384/0.147n   0.389/0.109n
dV/dt_f   0.393/0.106n   0.397/0.140n   0.389/93.739p
R_load = 50.000
[Rising Waveform]
R_fixture = 50.000
V_fixture = 1.200
V_fixture_min = 1.160
V_fixture_max = 1.240
|  time   V(typ)   V(min)   V(max)
0s        510.2mV    498.2mV    543.2mV
377ps     510.2mV    498.2mV    549.6mV
413ps     509.9mV    498.2mV    618mV
479ps     519.7mV    497.9mV    936.7mV
523ps     608.2mV    499mV      1.076V
608ps     985mV      548.6mV    1.165V
716ps     1.137V     921.2mV    1.186V
816ps     1.159V     1.089V     1.19V
1.036ns   1.164V     1.13V      1.191V
10ns      1.165V     1.132V     1.191V
[Falling Waveform]
R_fixture = 50.000
V_fixture = 1.200
V_fixture_min = 1.160
V_fixture_max = 1.240
|  time   V(typ)   V(min)   V(max)
0s        1.165V     1.132V     1.191V
378ps     1.164V     1.132V     1.191V
483ps     1.162V     1.133V     781.3mV
535ps     1.034V     1.136V     636mV
601ps     758.5mV    1.1V       574.1mV
657ps     610.8mV    959.7mV    556.6mV
732ps     542.9mV    731.2mV    548.2mV
862ps     517.1mV    544.6mV    544.4mV
1.132ns   510.9mV    502.8mV    543.4mV
10ns      510.2mV    498.2mV    543.2mV
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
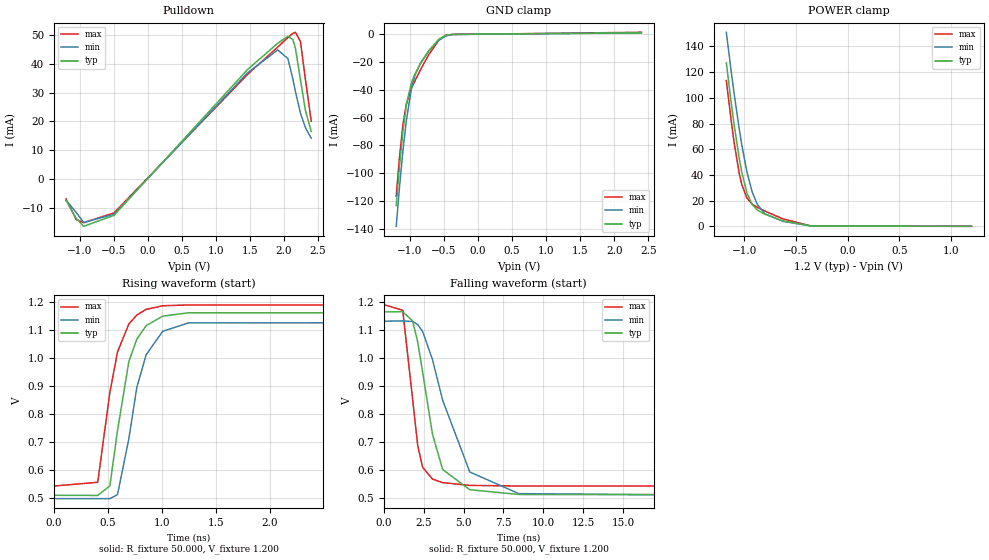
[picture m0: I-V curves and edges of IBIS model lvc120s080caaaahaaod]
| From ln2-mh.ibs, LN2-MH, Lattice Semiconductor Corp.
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|   Model lvc120s080caaaahaaod
[Model] lvc120s080caaaahaaod
Model_type I/O_open_drain
Polarity   Non-Inverting
Enable   Active-Low
Vinl =  0.420V
Vinh =  0.780V
Vmeas =  0.600V
Cref =  0.0F
Rref =  100
Vref =  1.20V
C_comp   2.000pF   1.500pF   2.500pF
[Temperature Range]   25.000   0.125k   -40.000
[Voltage Range]   1.200V   1.160V   1.240V
[C Comp Corner]
C_comp   2.000pF   1.500pF   2.500pF
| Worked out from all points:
|   slope of the pulldown table from 0 to 0.18 V, typ, clamps not added: 38.3 ohm
|   GND clamp passes 1 mA (typ) near -0.47 V on its own axis
|   POWER clamp passes 1 mA (typ) near -0.46 V on its own axis
|   rising waveform, R_fixture 50.000, V_fixture 1.200: 20-80 % time 174ps typ, 186ps min, 168ps max; typ from 0.51 V to 1.16 V
|   falling waveform, R_fixture 50.000, V_fixture 1.200: 20-80 % time 1.23ns typ, 2.02ns min, 700ps max; typ from 1.16 V to 0.51 V
[Pulldown]
|Voltage   I(typ)   I(min)   I(max)
-1.2V     -7.419mA   -7.326mA   -6.854mA
-1.052V   -13.57mA   -11.52mA   -13.99mA
-941mV    -16.34mA   -14.99mA   -15.09mA
-497mV    -12.55mA   -12.17mA   -11.71mA
1.464V    37.98mA    36.83mA    36.29mA
1.908V    47.11mA    44.8mA     45.8mA
2.056V    49.53mA    41.86mA    49.06mA
2.13V     48.33mA    34.77mA    50.55mA
2.167V    45.51mA    30.47mA    50.92mA
2.241V    34.59mA    22.92mA    47.79mA
2.315V    23.77mA    17.84mA    34.5mA
2.4V      16.53mA    14.17mA    20.13mA
[GND_clamp]
|Voltage   I(typ)   I(min)   I(max)
-1.2V     -123mA     -137.9mA   -116.3mA
-1.15V    -93.77mA   -109mA     -87.45mA
-1.1V     -69.04mA   -83.2mA    -64.7mA
-1.05V    -50.52mA   -61.66mA   -50.16mA
-975mV    -34.68mA   -39.02mA   -38.92mA
-925mV    -28.78mA   -29.88mA   -33.66mA
-850mV    -22.06mA   -21.38mA   -26.4mA
-725mV    -12.54mA   -12.25mA   -15.19mA
-575mV    -3.931mA   -4.562mA   -4.668mA
-475mV    -1.083mA   -1.617mA   -1.164mA
-375mV    -415.4uA   -497uA     -482.7uA
2.4V      768.5uA    596.7uA    1.09mA
[POWER_clamp]
|Voltage   I(typ)   I(min)   I(max)
-1.175V   127.2mA    151mA      113.4mA
-1.125V   94.42mA    118.8mA    80.34mA
-1.1V     79.34mA    103.6mA    65.54mA
-1.05V    52.82mA    75.75mA    41.2mA
-1.025V   41.91mA    63.3mA     32.44mA
-975mV    25.85mA    42.18mA    21.92mA
-925mV    17.02mA    26.81mA    17.31mA
-875mV    12.68mA    17.07mA    14.77mA
-800mV    9.315mA    9.719mA    11.8mA
-625mV    4.252mA    3.803mA    5.726mA
-350mV    125.8uA    261.6uA    148.8uA
1.2V      0A         0A         0A
[Ramp]
| variable   typ   min   max
dV/dt_r   0.410/1.501n   0.384/2.212n   0.389/1.006n
dV/dt_f   0.393/1.229n   0.397/2.018n   0.389/0.700n
R_load = 50.000
[Rising Waveform]
R_fixture = 50.000
V_fixture = 1.200
V_fixture_min = 1.160
V_fixture_max = 1.240
|  time   V(typ)   V(min)   V(max)
0s        510.2mV    498.2mV    543.2mV
407ps     509.7mV    498.3mV    556.7mV
519ps     544mV      498.1mV    877.5mV
590ps     741.3mV    512.7mV    1.022V
695ps     987.9mV    712.1mV    1.122V
769ps     1.068V     896.1mV    1.154V
855ps     1.116V     1.012V     1.174V
1.009ns   1.15V      1.096V     1.187V
1.249ns   1.162V     1.126V     1.19V
50ns      1.165V     1.132V     1.191V
[Falling Waveform]
R_fixture = 50.000
V_fixture = 1.200
V_fixture_min = 1.160
V_fixture_max = 1.240
|  time   V(typ)   V(min)   V(max)
0s        1.165V     1.132V     1.191V
1.179ns   1.166V     1.133V     1.171V
1.798ns   1.133V     1.131V     854.5mV
2.118ns   1.058V     1.12V      688.3mV
2.428ns   949.8mV    1.095V     610.2mV
3.046ns   728mV      995mV      568.1mV
3.686ns   602.4mV    849.6mV    555.5mV
5.386ns   530.3mV    593.5mV    545.7mV
8.462ns   513.2mV    516.2mV    543.4mV
50ns      510.2mV    498.2mV    543.2mV
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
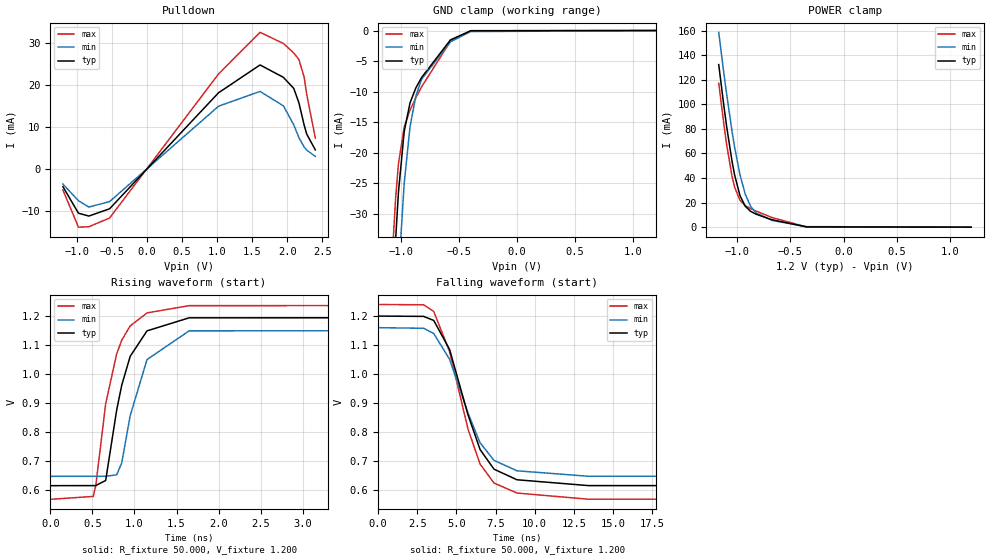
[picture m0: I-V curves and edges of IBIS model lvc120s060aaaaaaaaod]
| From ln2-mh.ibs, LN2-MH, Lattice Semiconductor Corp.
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|   Model lvc120s060aaaaaaaaod
[Model] lvc120s060aaaaaaaaod
Model_type I/O_open_drain
Polarity   Non-Inverting
Enable   Active-Low
Vinl =  0.420V
Vinh =  0.780V
Vmeas =  0.600V
Cref =  0.0F
Rref =  1000
Vref =  1.20V
C_comp   2.000pF   1.500pF   2.500pF
[Temperature Range]   25.000   0.125k   -40.000
[Voltage Range]   1.200V   1.160V   1.240V
[C Comp Corner]
C_comp   2.000pF   1.500pF   2.500pF
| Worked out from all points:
|   slope of the pulldown table from 0 to 0.18 V, typ, clamps not added: 53.5 ohm
|   GND clamp passes 1 mA (typ) near -0.54 V on its own axis
|   POWER clamp passes 1 mA (typ) near -0.43 V on its own axis
|   rising waveform, R_fixture 50.000, V_fixture 1.200: 20-80 % time 267ps typ, 277ps min, 259ps max; typ from 0.615 V to 1.2 V
|   falling waveform, R_fixture 50.000, V_fixture 1.200: 20-80 % time 2.01ns typ, 2.15ns min, 1.99ns max; typ from 1.2 V to 0.615 V
[Pulldown]
|Voltage   I(typ)   I(min)   I(max)
-1.2V     -4.218mA   -3.61mA    -5.008mA
-978mV    -10.55mA   -7.576mA   -13.87mA
-830mV    -11.23mA   -9.086mA   -13.77mA
-534mV    -9.495mA   -7.783mA   -11.7mA
1.02V     18.13mA    14.93mA    22.61mA
1.612V    24.75mA    18.45mA    32.52mA
1.945V    21.8mA     15.01mA    29.86mA
2.093V    19.16mA    10.48mA    27.61mA
2.167V    15.7mA     7.412mA    26.02mA
2.241V    10.43mA    5.22mA     21.84mA
2.278V    8.277mA    4.472mA    17.71mA
2.4V      4.534mA    2.978mA    7.355mA
[GND_clamp]
|Voltage   I(typ)   I(min)   I(max)
-1.2V     -115.8mA   -133.1mA   -106.7mA
-1.1V     -56.13mA   -73.78mA   -46.76mA
-1.075V   -44.35mA   -61.25mA   -35.92mA
-1.05V    -34.39mA   -49.96mA   -27.58mA
-1.025V   -26.47mA   -40.07mA   -21.79mA
-975mV    -16.49mA   -24.96mA   -15.78mA
-925mV    -11.84mA   -15.75mA   -13.01mA
-875mV    -9.407mA   -10.74mA   -11.02mA
-825mV    -7.688mA   -7.964mA   -9.21mA
-575mV    -1.526mA   -1.839mA   -1.756mA
-400mV    -41.92uA   -170.5uA   -22.66uA
1.2V      2.804pA    5.169nA    0A
[POWER_clamp]
|Voltage   I(typ)   I(min)   I(max)
-1.175V   132.4mA    158.7mA    117.3mA
-1.125V   97.66mA    124.2mA    82.52mA
-1.1V     81.7mA     108mA      66.94mA
-1.05V    53.7mA     78.16mA    41.43mA
-1.025V   42.27mA    64.92mA    32.37mA
-975mV    25.7mA     42.62mA    21.86mA
-925mV    16.96mA    26.72mA    17.53mA
-875mV    12.88mA    16.98mA    15.14mA
-825mV    10.61mA    11.65mA    13.19mA
-675mV    6.055mA    5.5mA      7.862mA
-350mV    219.1uA    435.6uA    237.4uA
1.2V      0A         0A         0A
[Ramp]
| variable   typ   min   max
dV/dt_r   0.351/2.008n   0.303/2.247n   0.405/1.911n
dV/dt_f   0.351/2.023n   0.308/2.156n   0.403/2.004n
R_load = 50.000
[Rising Waveform]
R_fixture= 50.000
V_fixture= 1.200
V_fixture_min= 1.160
V_fixture_max= 1.240
|time   V(typ)   V(min)   V(max)
0s        614.9mV    647mV      567.8mV
510ps     615.2mV    647.1mV    577.8mV
540ps     615.2mV    647.2mV    614.2mV
658ps     632.8mV    647.3mV    897.5mV
789ps     876.2mV    652.6mV    1.07V
849ps     961.7mV    693.6mV    1.117V
949ps     1.061V     856.1mV    1.166V
1.149ns   1.149V     1.05V      1.211V
1.649ns   1.194V     1.149V     1.236V
50ns      1.2V       1.16V      1.24V
[Falling Waveform]
R_fixture= 50.000
V_fixture= 1.200
V_fixture_min= 1.160
V_fixture_max= 1.240
|time   V(typ)   V(min)   V(max)
0s        1.2V       1.16V      1.24V
2.903ns   1.199V     1.158V     1.239V
3.551ns   1.185V     1.14V      1.216V
4.563ns   1.085V     1.051V     1.077V
5.743ns   858.9mV    865.2mV    809.7mV
6.513ns   739.5mV    762.8mV    689.5mV
7.403ns   671.8mV    702.2mV    624mV
8.873ns   635.3mV    666.2mV    589.5mV
13.43ns   615.2mV    647.4mV    568.2mV
50ns      614.9mV    646.9mV    567.8mV
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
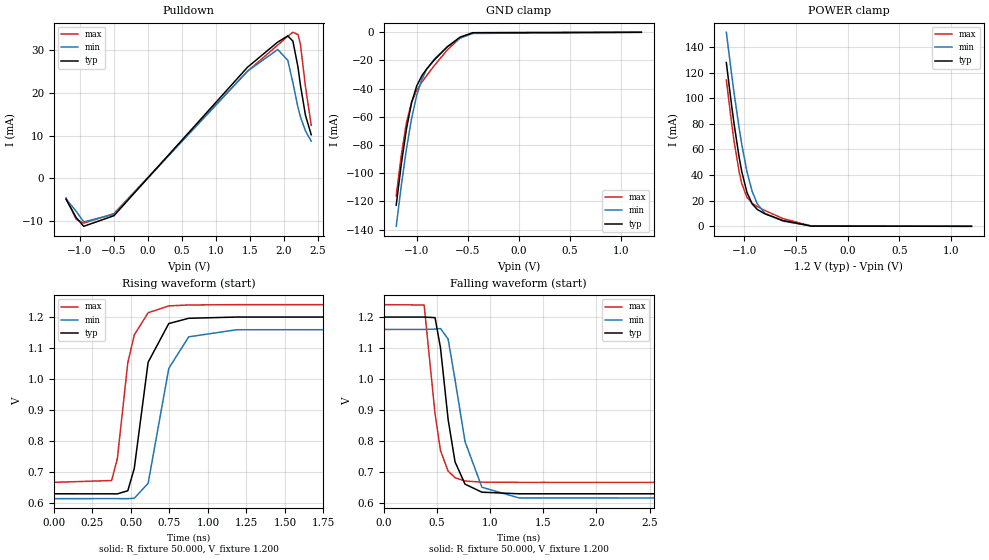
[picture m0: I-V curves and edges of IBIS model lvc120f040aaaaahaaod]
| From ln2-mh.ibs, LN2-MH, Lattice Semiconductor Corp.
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|   Model lvc120f040aaaaahaaod
[Model] lvc120f040aaaaahaaod
Model_type I/O_open_drain
Polarity   Non-Inverting
Enable   Active-Low
Vinl =  0.420V
Vinh =  0.780V
Vmeas =  0.600V
Cref =  0.0F
Rref =  1000
Vref =  1.20V
C_comp   2.000pF   1.500pF   2.500pF
[Temperature Range]   25.000   0.125k   -40.000
[Voltage Range]   1.200V   1.160V   1.240V
[C Comp Corner]
C_comp   2.000pF   1.500pF   2.500pF
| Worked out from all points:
|   slope of the pulldown table from 0 to 0.18 V, typ, clamps not added: 54.8 ohm
|   GND clamp passes 1 mA (typ) near -0.50 V on its own axis
|   POWER clamp passes 1 mA (typ) near -0.45 V on its own axis
|   rising waveform, R_fixture 50.000, V_fixture 1.200: 20-80 % time 97.8ps typ, 120ps min, 91ps max; typ from 0.629 V to 1.2 V
|   falling waveform, R_fixture 50.000, V_fixture 1.200: 20-80 % time 125ps typ, 168ps min, 105ps max; typ from 1.2 V to 0.629 V
[Pulldown]
|Voltage   I(typ)   I(min)   I(max)
-1.2V     -4.918mA   -4.823mA   -4.595mA
-1.052V   -9.159mA   -7.709mA   -9.593mA
-941mV    -11.22mA   -10.19mA   -10.48mA
-497mV    -8.735mA   -8.416mA   -8.241mA
1.464V    26mA       25.09mA    25.06mA
1.908V    31.89mA    30.15mA    31.19mA
2.056V    33.33mA    27.61mA    33.27mA
2.13V     32.13mA    22.4mA     34.18mA
2.204V    26.15mA    16.69mA    33.68mA
2.241V    21.84mA    14.4mA     31.42mA
2.315V    14.77mA    11.09mA    21.5mA
2.4V      10.2mA     8.713mA    12.39mA
[GND_clamp]
|Voltage   I(typ)   I(min)   I(max)
-1.2V     -122.7mA   -137.7mA   -116.1mA
-1.15V    -93.51mA   -108.7mA   -87.11mA
-1.1V     -68.71mA   -82.95mA   -64.25mA
-1.05V    -50.11mA   -61.37mA   -49.6mA
-1V       -38.2mA    -44.91mA   -41.31mA
-950mV    -30.97mA   -33.58mA   -35.58mA
-900mV    -25.86mA   -26.14mA   -30.55mA
-825mV    -19.51mA   -18.84mA   -23.44mA
-700mV    -10.31mA   -10.31mA   -12.51mA
-575mV    -3.428mA   -4.153mA   -4.057mA
-450mV    -324.6uA   -816.9uA   -269.6uA
1.2V      0A         0A         0A
[POWER_clamp]
|Voltage   I(typ)   I(min)   I(max)
-1.175V   127.9mA    151.5mA    114.3mA
-1.125V   95.1mA     119.3mA    81.28mA
-1.1V     80mA       104.1mA    66.45mA
-1.05V    53.45mA    76.24mA    42.06mA
-1.025V   42.52mA    63.79mA    33.25mA
-975mV    26.41mA    42.63mA    22.64mA
-925mV    17.53mA    27.24mA    17.96mA
-875mV    13.14mA    17.46mA    15.36mA
-800mV    9.702mA    10.06mA    12.29mA
-625mV    4.476mA    4.013mA    6.017mA
-350mV    147.7uA    296.5uA    176.7uA
1.2V      0A         0A         0A
[Ramp]
| variable   typ   min   max
dV/dt_r   0.337/0.137n   0.313/0.172n   0.338/0.123n
dV/dt_f   0.343/0.125n   0.328/0.169n   0.344/0.105n
R_load = 50.000
[Rising Waveform]
R_fixture= 50.000
V_fixture= 1.200
V_fixture_min= 1.160
V_fixture_max= 1.240
|time   V(typ)   V(min)   V(max)
0s        629.1mV    613.5mV    666.1mV
375ps     629mV      613.6mV    671.9mV
412ps     628.8mV    613.6mV    741.9mV
480ps     638.9mV    613.3mV    1.052V
522ps     711mV      614.6mV    1.142V
612ps     1.054V     663mV      1.214V
746ps     1.179V     1.034V     1.236V
875ps     1.196V     1.136V     1.239V
1.186ns   1.2V       1.159V     1.24V
10ns      1.2V       1.16V      1.24V
[Falling Waveform]
R_fixture= 50.000
V_fixture= 1.200
V_fixture_min= 1.160
V_fixture_max= 1.240
|time   V(typ)   V(min)   V(max)
0s        1.2V       1.16V      1.24V
378ps     1.2V       1.16V      1.239V
481ps     1.198V     1.161V     887.7mV
532ps     1.101V     1.163V     769.1mV
604ps     869.1mV    1.129V     702.4mV
669ps     732.4mV    997.7mV    681.1mV
763ps     660.4mV    797.8mV    670.6mV
922ps     634.5mV    650.4mV    666.9mV
1.269ns   629.3mV    616.1mV    666.2mV
10ns      629mV      613.5mV    666.1mV
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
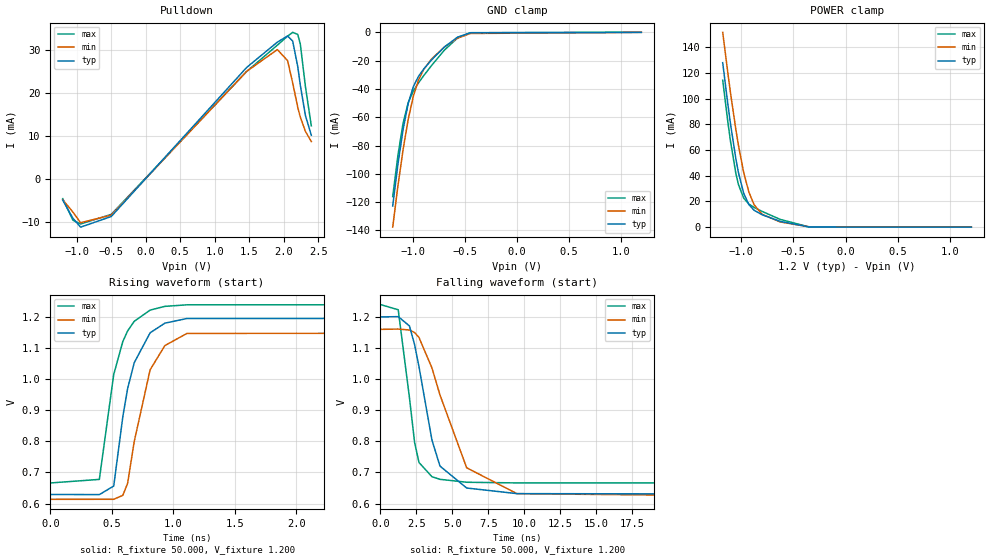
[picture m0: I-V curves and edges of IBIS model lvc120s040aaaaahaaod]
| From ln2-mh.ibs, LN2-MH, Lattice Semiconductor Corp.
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|   Model lvc120s040aaaaahaaod
[Model] lvc120s040aaaaahaaod
Model_type I/O_open_drain
Polarity   Non-Inverting
Enable   Active-Low
Vinl =  0.420V
Vinh =  0.780V
Vmeas =  0.600V
Cref =  0.0F
Rref =  1000
Vref =  1.20V
C_comp   2.000pF   1.500pF   2.500pF
[Temperature Range]   25.000   0.125k   -40.000
[Voltage Range]   1.200V   1.160V   1.240V
[C Comp Corner]
C_comp   2.000pF   1.500pF   2.500pF
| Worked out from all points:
|   slope of the pulldown table from 0 to 0.18 V, typ, clamps not added: 54.8 ohm
|   GND clamp passes 1 mA (typ) near -0.50 V on its own axis
|   POWER clamp passes 1 mA (typ) near -0.45 V on its own axis
|   rising waveform, R_fixture 50.000, V_fixture 1.200: 20-80 % time 165ps typ, 181ps min, 157ps max; typ from 0.629 V to 1.2 V
|   falling waveform, R_fixture 50.000, V_fixture 1.200: 20-80 % time 1.44ns typ, 2.4ns min, 837ps max; typ from 1.2 V to 0.629 V
[Pulldown]
|Voltage   I(typ)   I(min)   I(max)
-1.2V     -4.918mA   -4.823mA   -4.595mA
-1.052V   -9.159mA   -7.709mA   -9.593mA
-941mV    -11.22mA   -10.19mA   -10.48mA
-497mV    -8.735mA   -8.416mA   -8.241mA
1.464V    26mA       25.09mA    25.06mA
1.908V    31.89mA    30.15mA    31.19mA
2.056V    33.33mA    27.6mA     33.27mA
2.13V     32.13mA    22.4mA     34.18mA
2.204V    26.15mA    16.69mA    33.68mA
2.241V    21.84mA    14.4mA     31.42mA
2.315V    14.77mA    11.09mA    21.5mA
2.4V      10.2mA     8.712mA    12.39mA
[GND_clamp]
|Voltage   I(typ)   I(min)   I(max)
-1.2V     -122.7mA   -137.7mA   -116.1mA
-1.15V    -93.51mA   -108.7mA   -87.11mA
-1.1V     -68.71mA   -82.95mA   -64.25mA
-1.05V    -50.11mA   -61.37mA   -49.6mA
-1V       -38.2mA    -44.91mA   -41.31mA
-950mV    -30.97mA   -33.58mA   -35.58mA
-900mV    -25.86mA   -26.14mA   -30.55mA
-825mV    -19.51mA   -18.84mA   -23.44mA
-700mV    -10.31mA   -10.31mA   -12.51mA
-575mV    -3.428mA   -4.153mA   -4.057mA
-450mV    -324.6uA   -816.9uA   -269.6uA
1.2V      0A         0A         0A
[POWER_clamp]
|Voltage   I(typ)   I(min)   I(max)
-1.175V   127.9mA    151.5mA    114.3mA
-1.125V   95.1mA     119.3mA    81.28mA
-1.1V     80mA       104.1mA    66.45mA
-1.05V    53.45mA    76.24mA    42.06mA
-1.025V   42.52mA    63.79mA    33.25mA
-975mV    26.41mA    42.63mA    22.64mA
-925mV    17.53mA    27.24mA    17.96mA
-875mV    13.14mA    17.46mA    15.36mA
-800mV    9.702mA    10.06mA    12.29mA
-625mV    4.476mA    4.013mA    6.017mA
-350mV    147.7uA    296.5uA    176.7uA
1.2V      0A         0A         0A
[Ramp]
| variable   typ   min   max
dV/dt_r   0.337/1.899n   0.313/2.799n   0.338/1.264n
dV/dt_f   0.343/1.444n   0.328/2.401n   0.344/0.837n
R_load = 50.000
[Rising Waveform]
R_fixture= 50.000
V_fixture= 1.200
V_fixture_min= 1.160
V_fixture_max= 1.240
|time   V(typ)   V(min)   V(max)
0s        629.1mV    613.5mV    666.1mV
399ps     628.7mV    613.6mV    677.6mV
516ps     656.2mV    613.6mV    1.015V
590ps     879.3mV    626.3mV    1.121V
629ps     969.9mV    665.1mV    1.155V
683ps     1.053V     799.9mV    1.186V
812ps     1.149V     1.03V      1.222V
932ps     1.18V      1.108V     1.234V
1.112ns   1.195V     1.147V     1.239V
50ns      1.2V       1.16V      1.24V
[Falling Waveform]
R_fixture= 50.000
V_fixture= 1.200
V_fixture_min= 1.160
V_fixture_max= 1.240
|time   V(typ)   V(min)   V(max)
0s        1.2V       1.16V      1.24V
1.246ns   1.201V     1.161V     1.223V
2.026ns   1.171V     1.158V     940.1mV
2.382ns   1.111V     1.15V      796.7mV
2.687ns   1.04V      1.134V     732mV
3.586ns   804.1mV    1.036V     686.3mV
4.146ns   720.3mV    948.9mV    677.8mV
5.996ns   649.9mV    715mV      668.4mV
9.492ns   631.8mV    631.7mV    666.3mV
50ns      629mV      613.5mV    666.1mV
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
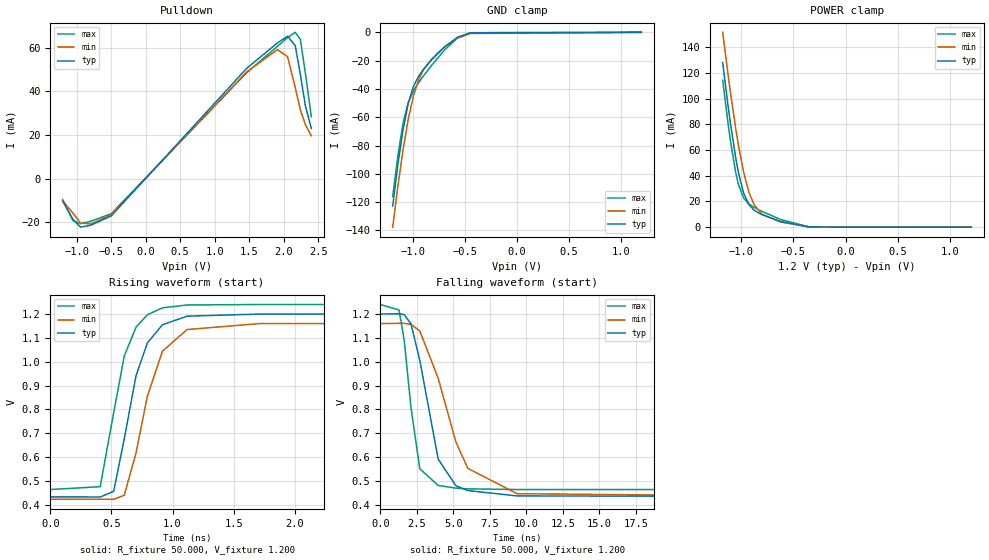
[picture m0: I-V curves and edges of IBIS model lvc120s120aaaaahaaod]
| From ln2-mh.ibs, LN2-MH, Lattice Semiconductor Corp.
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|   Model lvc120s120aaaaahaaod
[Model] lvc120s120aaaaahaaod
Model_type I/O_open_drain
Polarity   Non-Inverting
Enable   Active-Low
Vinl =  0.420V
Vinh =  0.780V
Vmeas =  0.600V
Cref =  0.0F
Rref =  1000
Vref =  1.20V
C_comp   2.000pF   1.500pF   2.500pF
[Temperature Range]   25.000   0.125k   -40.000
[Voltage Range]   1.200V   1.160V   1.240V
[C Comp Corner]
C_comp   2.000pF   1.500pF   2.500pF
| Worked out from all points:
|   slope of the pulldown table from 0 to 0.18 V, typ, clamps not added: 28.2 ohm
|   GND clamp passes 1 mA (typ) near -0.50 V on its own axis
|   POWER clamp passes 1 mA (typ) near -0.45 V on its own axis
|   rising waveform, R_fixture 50.000, V_fixture 1.200: 20-80 % time 192ps typ, 204ps min, 178ps max; typ from 0.433 V to 1.2 V
|   falling waveform, R_fixture 50.000, V_fixture 1.200: 20-80 % time 1.41ns typ, 2.26ns min, 811ps max; typ from 1.2 V to 0.433 V
[Pulldown]
|Voltage   I(typ)   I(min)   I(max)
-1.2V     -10.29mA   -10.12mA   -9.55mA
-1.052V   -18.66mA   -15.79mA   -19.23mA
-941mV    -22.22mA   -20.34mA   -20.62mA
-793mV    -21.33mA   -20.77mA   -19.52mA
-497mV    -17.06mA   -16.46mA   -16.05mA
1.464V    50.6mA     48.95mA    48.6mA
1.908V    62.24mA    59.17mA    60.67mA
2.056V    65.34mA    55.96mA    64.72mA
2.167V    61.02mA    41.77mA    67.12mA
2.241V    47.77mA    31.68mA    63.89mA
2.315V    33.27mA    24.7mA     48.16mA
2.4V      23.04mA    19.67mA    28.43mA
[GND_clamp]
|Voltage   I(typ)   I(min)   I(max)
-1.2V     -122.7mA   -137.7mA   -116.1mA
-1.15V    -93.51mA   -108.7mA   -87.11mA
-1.1V     -68.71mA   -82.95mA   -64.25mA
-1.05V    -50.11mA   -61.37mA   -49.6mA
-1V       -38.2mA    -44.91mA   -41.31mA
-950mV    -30.97mA   -33.58mA   -35.58mA
-900mV    -25.86mA   -26.14mA   -30.55mA
-825mV    -19.51mA   -18.84mA   -23.44mA
-700mV    -10.31mA   -10.31mA   -12.51mA
-575mV    -3.428mA   -4.153mA   -4.057mA
-450mV    -324.6uA   -816.9uA   -269.6uA
1.2V      0A         0A         0A
[POWER_clamp]
|Voltage   I(typ)   I(min)   I(max)
-1.175V   127.9mA    151.5mA    114.3mA
-1.125V   95.1mA     119.3mA    81.28mA
-1.1V     80mA       104.1mA    66.45mA
-1.05V    53.45mA    76.24mA    42.06mA
-1.025V   42.52mA    63.79mA    33.25mA
-975mV    26.41mA    42.63mA    22.64mA
-925mV    17.53mA    27.24mA    17.96mA
-875mV    13.14mA    17.46mA    15.36mA
-800mV    9.702mA    10.06mA    12.29mA
-625mV    4.476mA    4.013mA    6.017mA
-350mV    147.7uA    296.5uA    176.7uA
1.2V      0A         0A         0A
[Ramp]
| variable   typ   min   max
dV/dt_r   0.458/1.722n   0.431/2.552n   0.462/1.111n
dV/dt_f   0.460/1.416n   0.442/2.272n   0.466/0.811n
R_load = 50.000
[Rising Waveform]
R_fixture= 50.000
V_fixture= 1.200
V_fixture_min= 1.160
V_fixture_max= 1.240
|time   V(typ)   V(min)   V(max)
0s        433.4mV    423.4mV    464.1mV
408ps     432.8mV    423.4mV    476mV
518ps     456.3mV    423mV      784.7mV
605ps     676.8mV    440.4mV    1.024V
701ps     941.4mV    617.2mV    1.145V
794ps     1.079V     855.3mV    1.197V
917ps     1.155V     1.044V     1.226V
1.118ns   1.191V     1.135V     1.238V
1.715ns   1.2V       1.16V      1.24V
50ns      1.2V       1.16V      1.24V
[Falling Waveform]
R_fixture= 50.000
V_fixture= 1.200
V_fixture_min= 1.160
V_fixture_max= 1.240
|time   V(typ)   V(min)   V(max)
0s        1.2V       1.16V      1.24V
1.285ns   1.201V     1.161V     1.217V
1.635ns   1.198V     1.161V     1.092V
2.107ns   1.158V     1.157V     806.6mV
2.707ns   1.006V     1.129V     551.4mV
3.966ns   591.9mV    930.6mV    481.6mV
5.176ns   480.4mV    664.3mV    470.4mV
5.993ns   460.2mV    553.4mV    467.4mV
9.366ns   437.7mV    447.2mV    464.4mV
50ns      433.4mV    423.4mV    464.1mV
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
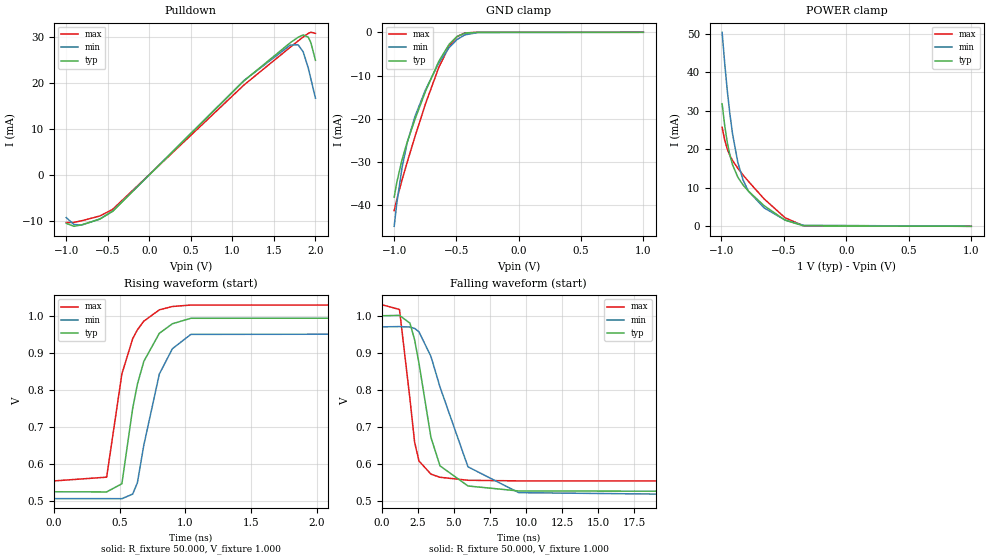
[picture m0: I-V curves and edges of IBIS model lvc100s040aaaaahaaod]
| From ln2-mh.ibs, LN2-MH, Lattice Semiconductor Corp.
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|   Model lvc100s040aaaaahaaod
[Model] lvc100s040aaaaahaaod
Model_type I/O_open_drain
Polarity   Non-Inverting
Enable   Active-Low
Vinl =  0.350V
Vinh =  0.650V
Vmeas =  0.500V
Cref =  0.0F
Rref =  1000
Vref =  1.00V
C_comp   2.000pF   1.500pF   2.500pF
[Temperature Range]   25.000   0.125k   -40.000
[Voltage Range]   1.000V   0.970V   1.030V
[C Comp Corner]
C_comp   2.000pF   1.500pF   2.500pF
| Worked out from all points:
|   slope of the pulldown table from 0 to 0.15 V, typ, clamps not added: 54.8 ohm
|   GND clamp passes 1 mA (typ) near -0.50 V on its own axis
|   POWER clamp passes 1 mA (typ) near -0.45 V on its own axis
|   rising waveform, R_fixture 50.000, V_fixture 1.000: 20-80 % time 166ps typ, 182ps min, 158ps max; typ from 0.524 V to 1 V
|   falling waveform, R_fixture 50.000, V_fixture 1.000: 20-80 % time 1.32ns typ, 2.33ns min, 757ps max; typ from 1 V to 0.524 V
[Pulldown]
|Voltage   I(typ)   I(min)   I(max)
-1V       -10.61mA   -9.357mA   -10.43mA
-907mV    -11.25mA   -10.87mA   -10.39mA
-814mV    -10.93mA   -10.96mA   -10.04mA
-597mV    -9.684mA   -9.668mA   -9.009mA
-442mV    -7.977mA   -7.964mA   -7.56mA
1.139V    20.47mA    20.54mA    19.56mA
1.697V    28.78mA    28.27mA    27.81mA
1.79V     29.96mA    28.35mA    29.15mA
1.852V    30.49mA    26.82mA    30.03mA
1.914V    29.99mA    23.22mA    30.83mA
1.945V    28.78mA    20.88mA    31.06mA
2V        24.95mA    16.69mA    30.83mA
[GND_clamp]
|Voltage   I(typ)   I(min)   I(max)
-1V       -38.12mA   -44.85mA   -41.21mA
-979mV    -34.68mA   -39.51mA   -38.64mA
-937mV    -29.43mA   -31.27mA   -34.13mA
-895mV    -25.33mA   -25.48mA   -29.97mA
-832mV    -20.01mA   -19.35mA   -24mA
-748mV    -13.6mA    -13.25mA   -16.46mA
-643mV    -6.759mA   -7.17mA    -8.178mA
-559mV    -2.781mA   -3.541mA   -3.248mA
-496mV    -972.8uA   -1.676mA   -1.012mA
-433mV    -198uA     -594.9uA   -143.9uA
-328mV    -6.321uA   -55.61uA   -1.827uA
1V        42.39pA    0A         0A
[POWER_clamp]
|Voltage   I(typ)   I(min)   I(max)
-995mV    31.81mA    50.36mA    25.7mA
-974mV    26.08mA    42.19mA    22.34mA
-953mV    21.65mA    35.04mA    20mA
-932mV    18.35mA    28.96mA    18.33mA
-911mV    15.92mA    23.9mA     17.05mA
-869mV    12.73mA    16.55mA    15.04mA
-827mV    10.71mA    11.99mA    13.31mA
-785mV    9.149mA    9.156mA    11.68mA
-659mV    5.357mA    4.783mA    7.128mA
-491mV    1.591mA    1.628mA    2.217mA
-344mV    125.7uA    266.7uA    146.2uA
1V        0A         0A         0A
[Ramp]
| variable   typ   min   max
dV/dt_r   0.280/1.398n   0.266/1.881n   0.289/0.971n
dV/dt_f   0.286/1.321n   0.279/2.332n   0.286/0.763n
R_load = 50.000
[Rising Waveform]
R_fixture= 50.000
V_fixture= 1.000
V_fixture_min= 0.970
V_fixture_max= 1.030
|time   V(typ)   V(min)   V(max)
0s        523.9mV    505.3mV    553.2mV
402ps     523.5mV    505.3mV    563.4mV
518ps     545.6mV    505.2mV    842.7mV
600ps     749mV      517.6mV    937.7mV
636ps     814.8mV    548.3mV    961.9mV
685ps     876.7mV    650.2mV    985.4mV
803ps     952.5mV    842.3mV    1.016V
902ps     978.3mV    910.7mV    1.025V
1.043ns   993.2mV    949.6mV    1.029V
50ns      1V         970mV      1.03V
[Falling Waveform]
R_fixture= 50.000
V_fixture= 1.000
V_fixture_min= 0.970
V_fixture_max= 1.030
|time   V(typ)   V(min)   V(max)
0s        1V         970mV      1.03V
1.228ns   1.001V     970.7mV    1.017V
1.956ns   979.9mV    969.5mV    774.2mV
2.278ns   934.7mV    965.8mV    657.8mV
2.577ns   872.1mV    956.7mV    607.3mV
3.407ns   671.1mV    890.1mV    571.6mV
4.037ns   594mV      807.1mV    563.1mV
5.972ns   539.6mV    591.4mV    555mV
9.493ns   526mV      521.5mV    553.3mV
50ns      523.9mV    505.2mV    553.2mV
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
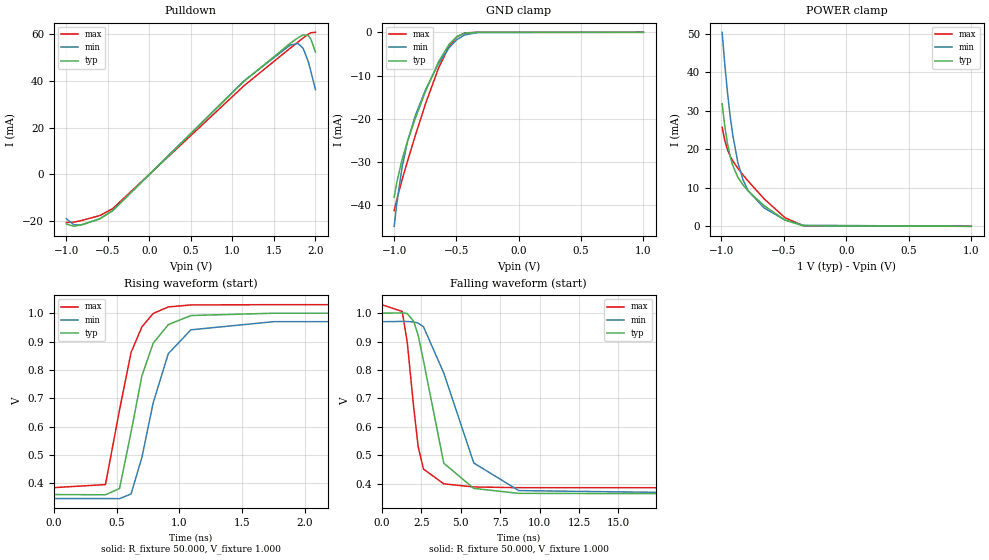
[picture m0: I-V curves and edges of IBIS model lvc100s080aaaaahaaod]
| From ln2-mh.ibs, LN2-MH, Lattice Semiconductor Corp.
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|   Model lvc100s080aaaaahaaod
[Model] lvc100s080aaaaahaaod
Model_type I/O_open_drain
Polarity   Non-Inverting
Enable   Active-Low
Vinl =  0.350V
Vinh =  0.650V
Vmeas =  0.500V
Cref =  0.0F
Rref =  1000
Vref =  1.00V
C_comp   2.000pF   1.500pF   2.500pF
[Temperature Range]   25.000   0.125k   -40.000
[Voltage Range]   1.000V   0.970V   1.030V
[C Comp Corner]
C_comp   2.000pF   1.500pF   2.500pF
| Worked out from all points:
|   slope of the pulldown table from 0 to 0.15 V, typ, clamps not added: 28.2 ohm
|   GND clamp passes 1 mA (typ) near -0.50 V on its own axis
|   POWER clamp passes 1 mA (typ) near -0.45 V on its own axis
|   rising waveform, R_fixture 50.000, V_fixture 1.000: 20-80 % time 192ps typ, 207ps min, 178ps max; typ from 0.361 V to 1 V
|   falling waveform, R_fixture 50.000, V_fixture 1.000: 20-80 % time 1.31ns typ, 2.23ns min, 746ps max; typ from 1 V to 0.361 V
[Pulldown]
|Voltage   I(typ)   I(min)   I(max)
-1V       -21.25mA   -18.95mA   -20.6mA
-907mV    -22.22mA   -21.6mA    -20.43mA
-814mV    -21.54mA   -21.62mA   -19.71mA
-597mV    -19mA      -18.98mA   -17.63mA
-442mV    -15.54mA   -15.54mA   -14.68mA
1.139V    39.83mA    40.02mA    37.93mA
1.697V    56.14mA    55.4mA     54.08mA
1.79V     58.51mA    56.05mA    56.67mA
1.852V    59.71mA    53.97mA    58.41mA
1.914V    59.45mA    48.22mA    60.03mA
1.945V    57.9mA     44.12mA    60.63mA
2V        52.35mA    36.29mA    60.84mA
[GND_clamp]
|Voltage   I(typ)   I(min)   I(max)
-1V       -38.12mA   -44.85mA   -41.21mA
-979mV    -34.68mA   -39.51mA   -38.64mA
-937mV    -29.43mA   -31.27mA   -34.13mA
-895mV    -25.33mA   -25.48mA   -29.97mA
-832mV    -20.01mA   -19.35mA   -24mA
-748mV    -13.6mA    -13.25mA   -16.46mA
-643mV    -6.759mA   -7.17mA    -8.178mA
-559mV    -2.781mA   -3.541mA   -3.248mA
-496mV    -972.8uA   -1.676mA   -1.012mA
-433mV    -198uA     -594.9uA   -143.9uA
-328mV    -6.321uA   -55.61uA   -1.827uA
1V        42.39pA    0A         0A
[POWER_clamp]
|Voltage   I(typ)   I(min)   I(max)
-995mV    31.81mA    50.36mA    25.7mA
-974mV    26.08mA    42.19mA    22.34mA
-953mV    21.65mA    35.04mA    20mA
-932mV    18.35mA    28.96mA    18.33mA
-911mV    15.92mA    23.9mA     17.05mA
-869mV    12.73mA    16.55mA    15.04mA
-827mV    10.71mA    11.99mA    13.31mA
-785mV    9.149mA    9.156mA    11.68mA
-659mV    5.357mA    4.783mA    7.128mA
-491mV    1.591mA    1.628mA    2.217mA
-344mV    125.7uA    266.7uA    146.2uA
1V        0A         0A         0A
[Ramp]
| variable   typ   min   max
dV/dt_r   0.381/1.162n   0.364/1.526n   0.391/0.775n
dV/dt_f   0.383/1.314n   0.374/2.238n   0.387/0.746n
R_load = 50.000
[Rising Waveform]
R_fixture= 50.000
V_fixture= 1.000
V_fixture_min= 0.970
V_fixture_max= 1.030
|time   V(typ)   V(min)   V(max)
0s        361mV      347.1mV    385.4mV
411ps     360.3mV    347.1mV    396.1mV
523ps     382.3mV    346.5mV    659mV
615ps     581mV      363.1mV    861.6mV
701ps     779mV      491.8mV    951.9mV
791ps     894.2mV    684.1mV    998.9mV
911ps     959.6mV    857.2mV    1.022V
1.091ns   991.7mV    941.4mV    1.029V
1.751ns   999.9mV    970.1mV    1.03V
50ns      1V         970mV      1.03V
[Falling Waveform]
R_fixture= 50.000
V_fixture= 1.000
V_fixture_min= 0.970
V_fixture_max= 1.030
|time   V(typ)   V(min)   V(max)
0s        1V         970mV      1.03V
1.297ns   1.001V     971mV      1.006V
1.617ns   998.7mV    970.7mV    897.5mV
2.027ns   971.2mV    969.2mV    667.8mV
2.307ns   922.6mV    965.1mV    530.9mV
2.646ns   832.4mV    952.2mV    451.3mV
3.932ns   471.9mV    789.3mV    399.4mV
5.832ns   383.4mV    472.8mV    388.4mV
8.686ns   365.8mV    375.5mV    385.8mV
50ns      361mV      347.1mV    385.4mV
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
